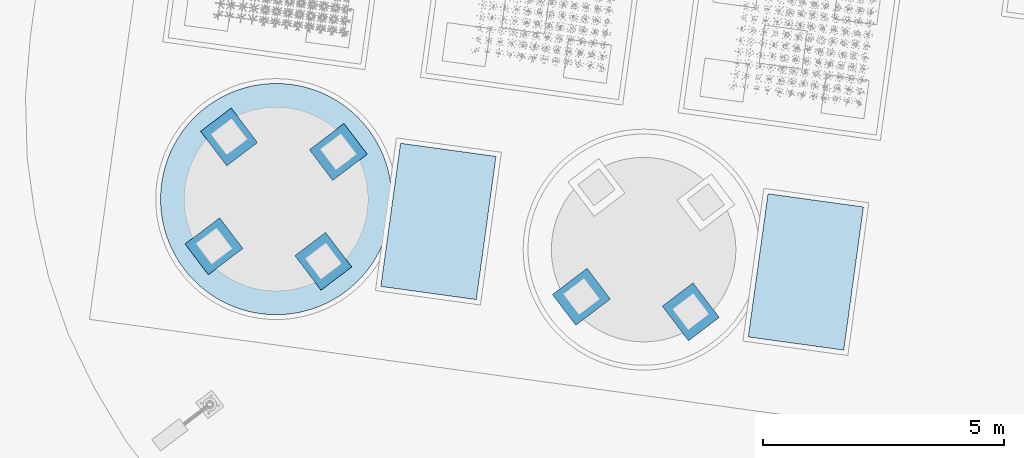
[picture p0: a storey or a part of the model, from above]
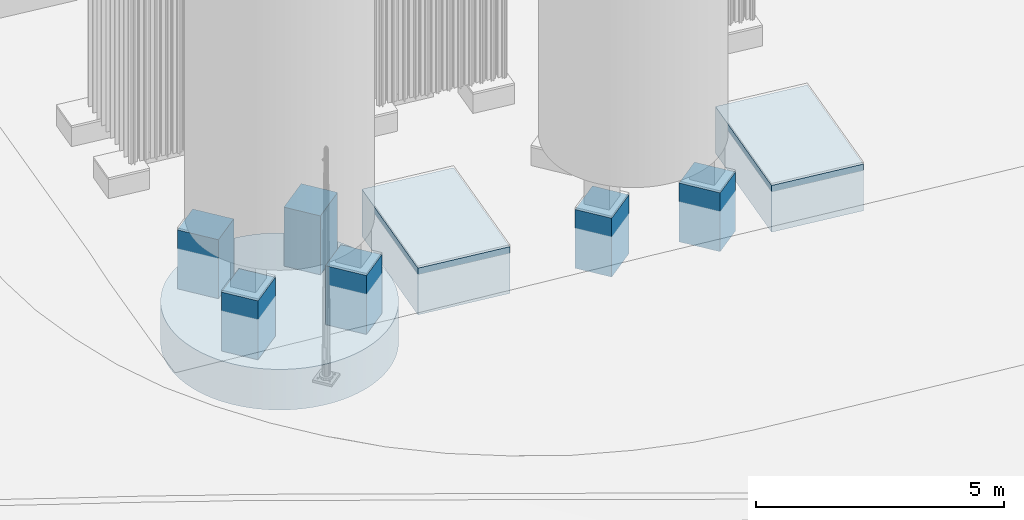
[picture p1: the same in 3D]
Properties of the parts of a building model (IFC4), part 1 of 134

# File
Description: Modelo BIM de planta completa con capas funcionales, componentes, acabados visuales y referencias geométricas identificadas.
File name: Jinhong_BIM.ifc
Time: 2026-09-07T22:02:33
Author: Equipo BIM de Jinhong
Organization: Jinhong Gas (España), S.L.
Written by: IfcOpenShell 0.8.5-1c5b825
Made in: IfcOpenShell 0.8.5-1c5b825
Authorization: Modelo de coordinación documental; pendiente de revisión profesional

# IfcProject, Planta de nitrógeno Jinhong — Mérida
Description: Reconstrucción BIM a partir de planos de arquitectura, estructura, urbanización y documentación de equipos. Información documentada, derivada y provisional diferenciada por elemento.; Document: Índice de tuberías de proceso; Fabricación y montaje de tuberías; Soldadura y ensayos no destructivos; Lavado y limpieza; Aislamiento térmico; Pintura; Pruebas de presión; Datos de líneas de proceso; Cuadro de aislamiento; Protección anticorrosiva; Materiales de tuberías; Implantación de equipos; Condiciones de cimentación; Planta general de tuberías de proceso; Plantas de tuberías por zonas; Índice de isométricos de proceso; Isométricos de proceso; Isométricos de agua; Isométricos del bastidor de proceso; Planta de estructuras metálicas; Soportes de equipos SL1201 y SL401/402; Soporte del bastidor de equipos; Soporte del bastidor de tuberías; Estructura de marquesina; Soportes especiales; Campana de aspiración; Soportes A01 y A02; Soportes estándar de tuberías; Plataformas de acceso; Escaleras de plataformas; Estructura de peldaños; Apertura automática de puerta; Plataforma móvil; Índice de tuberías de reserva; Fabricación y montaje de tuberías de reserva; Soldadura y ensayos no destructivos de reserva; Lavado y limpieza de reserva; Aislamiento térmico de reserva; Pintura de reserva; Pruebas de presión de reserva; Datos de líneas de reserva; Cuadro de aislamiento de reserva; Materiales de tuberías de reserva; Implantación de equipos de reserva; Condiciones de cimentación de reserva; Plantas de tuberías de reserva; Índice de isométricos de reserva; Isométricos de reserva; Isométricos del bastidor de reserva 1; Isométricos del bastidor de reserva 2; Planta de estructuras de reserva; Soportes A01 y A02 de reserva; Soportes especiales de reserva; Estructura del bastidor de reserva 1; Estructura del bastidor de reserva 2; Plano general del bastidor de reserva 1; Plano general del bastidor de reserva 2; Lista de soportes de reserva; Soportes estándar de reserva; Aislamiento de apoyos fríos; Índice de instrumentación; Diseño y montaje de instrumentación; Plantas generales de instrumentación; Plantas generales de instrumentación · copia de compatibilidad; Detalles de montaje de instrumentos; Distribución de aire de instrumentos; Puesta a tierra de instrumentos; Índice de planos eléctricos; Instrucciones eléctricas de diseño e instalación; Plano general eléctrico; Alumbrado de la caja fría; Esquema del cuadro de mantenimiento
JH_AlcanceDelModelo - Idioma: Español; Fase: Reconstrucción documental y coordinación preliminar; Limitaciones: Sin espacios interiores inventados ni redes MEP añadidas. Las prestaciones no verificadas se omiten.; CriterioDeMediciones: Cálculo de la geometría representada. Los volúmenes de envolventes y las dimensiones provisionales no son mediciones de obra, compra ni fabricación.; NúmeroDeElementos: 307

# IfcSite, Parcela industrial Jinhong
Description: Emplazamiento de la planta en Mérida; sistema de coordenadas ETRS89 / UTM 29N.
JH_Georreferenciacion - CRS: EPSG:25829; EsteDelOrigen: 729400 m; NorteDelOrigen: 4301550 m; CotaDelOrigen: 285 m; DatumVertical: Cotas de los planos; datum vertical pendiente de confirmación; Uso: Coordinación de la documentación disponible

# IfcBuilding (2)
Description: Edificio reconstruido a partir de planos; revisión documental y coordinación pendiente.
JH_DatosDelEdificio - CriterioDeSuperficie: Superficie exterior construida; no equivale a superficie útil ni a medición contractual; NoModelado: ["Particiones interiores con posición exacta, puertas interiores y aparatos sanitarios.","Instalaciones completas de agua, incendios, climatización, electricidad, cables e instrumentación.","Armaduras, placas y anclajes de conexión, detalle completo de correas y remates."]
Name | Document | IdentificadorDelEdificio | UsoDocumentado | CotaAbsolutaPavimentoTerminado (m) | SuperficieConstruidaDocumentada (m2) | FuenteDeSuperficie | Estado | SuperficieUtilDocumentada (m2) | IncidenciasPendientes
Sala de bombas contra incendios | Planos de arquitectura de la sala de bombas contra incendios | pump_house | Instalaciones de bombeo de agua contra incendios | 286.25 | 83.64 | {"documentId":"ARQ-SB-20260710","title":"Planos de arquitectura de la sala de bombas contra incendios","date":"2026-07-10","sheet":"A101 / p. 3; plano general URB-20260731, U004 / p. 5"} | Edificio representado en planos de arquitectura y estructura | 76.44 | ["Los cajetines de A108 y A201 conservan referencias de otro proyecto; la geometría se ha contrastado con A101.","A201 indica 300 mm de C25 sobre 100 mm de limpieza; el cuadro de materiales indica 200 mm de HA-25 sobre 80 mm de limpieza. El cajetín de A201 conserva una referencia a YUNENG ajena a este proyecto.","A110 indica antepecho de 1500 mm; otras secciones y alzados sugieren una cota menor. A110 titula la ventana C1290 y el cuadro A109 la identifica como C1226.","Las secciones también indican 284,75 m en la zona de zócalo y viga, frente a 284,85 m en la nota general. Ambas cotas requieren conciliación.","Los detalles de anclaje indican 10M30 y 12M30; la placa de base presenta cotas 650 y 750 mm no conciliadas. Anclajes y placas no modelados.","Depósito contra incendios: diámetro exterior de 6,50 m en el plano general, radio de 3,35 m en arquitectura y diámetro de cimentación de 6,00 m en estructura; requieren conciliación."]
Edificio de oficinas | Planos de arquitectura del edificio de oficinas | office | Administración, oficinas y servicios higiénicos | 285.95 | 200 | {"documentId":"ARQ-OF-20260710","title":"Planos de arquitectura del edificio de oficinas","date":"2026-07-10","sheet":"A101 / p. 3; plano general URB-20260731, U004 / p. 5"} | Oficina representada en el plano general; decisión de mantenerla pendiente de confirmación | 183.25 | ["El plano general de 2026-07-31 mantiene el edificio de oficinas de 200 m², mientras documentación anterior indica su supresión. Se conserva lo dibujado, pendiente de confirmación de la propiedad y del equipo de diseño.","Cubierta: arquitectura indica +4,400 m y el detalle estructural +4,450 m; espesores de placa 250 + 50 mm y 200 + 50 mm respectivamente. Se adopta el detalle estructural.","Pilares a +5,000 m según B102 y encuentro con cubierta a +4,450 m pendientes de coordinación.","Capas de fachada y cadena sur de huecos con diferencia de 100 mm pendientes de cotejo con CAD."]

# IfcBuildingStorey (2)
Description: Nivel de referencia del edificio. Las coordenadas de la geometría se conservan.
JH_DatosDelNivel - Nombre: Planta baja; Fuente: Planos de arquitectura y plano general U004
Name | In | Elevation (m) = CotaRelativaAlOrigen (m) | Document | CotaAbsolutaPavimentoTerminado (m)
Planta baja | Sala de bombas contra incendios | 1.25 | Planos de arquitectura de la sala de bombas contra incendios | 286.25
Planta baja | Edificio de oficinas | 0.95 | Planos de arquitectura del edificio de oficinas | 285.95

# IfcAnnotation: Plazas de aparcamiento · disposición ilustrativa
In: Parcela industrial Jinhong
Description: Entorno de coordinación: trazados derivados de las fuentes indicadas por elemento; cotas, espesores, acabados y mobiliario orientativos cuando no están documentados. No acredita propiedad, servidumbres ni cantidades de obra y no es una base de construcción.; Document: Indicación del cliente · entorno de 200 m con aparcamientos y luminarias ilustrativos; Entorno de Expacio Mérida · Catastro INSPIRE, PNOA y levantamiento Berrio; Levantamiento Berrio · parcelas I-27 Vial 3 e I-18 Vial 4; IGN · ortofotografía PNOA de máxima actualidad; Group: BIM · Entorno · aparcamientos y luminarias
JH_InformacionBIM - buildingId: context; buildingName: Entorno exterior de la parcela; level: Exterior · contexto de 200 m; category: Plazas de aparcamiento · disposición ilustrativa; ifcClass: IfcAnnotation; status: provisional; source: {"documentId":"JH-CLIENT-CONTEXT-20260909","title":"Indicación del cliente · entorno de 200 m con aparcamientos y luminarias ilustrativos","date":"2026-09-09","note":"Distribución aproximada autorizada. No acredita la posición ni el número real de plazas o farolas existentes."}; material: {"name":"Marcas de aparcamiento","status":"provisional","source":"Acabado visual aproximado; no especificación de proyecto."}; appearance: {"profileId":"ctx_mark","name":"Marcas de aparcamiento","status":"criterio_visual","basis":"Acabado de contexto orientativo, sin especificación de obra."}; dimensions: {"documented":[],"assumed":[{"label":"Largo de plaza","value":5.5,"unit":"m"},{"label":"Ancho de plaza","value":2.2,"unit":"m"},{"label":"Plazas representadas","value":16,"unit":"ud"}],"geometry":[]}; classification: {"layerId":"context_furniture","layerName":"Entorno · aparcamientos y luminarias","function":"Plazas de aparcamiento · disposición ilustrativa"}; visualLayer: {"id":"context_furniture","name":"Entorno · aparcamientos y luminarias","defaultVisible":false}; representationKind: entorno_ilustrativo; quantityEligible: no; positioning: {"Sistema":"ETRS89 / UTM 29N · metros","Origen del modelo":"X 729400 · Y 4301550 · Z 285 m","Alcance":"Hasta 200 m desde el lindero del proyecto; solo exterior de parcela","Planta":"Distribución ilustrativa autorizada","Altimetría":"Plano ajustado a 213 puntos XYZ de aceras, extrapolado al resto del contexto; no es un MDT levantado"}; issues: ["Contexto para lectura del emplazamiento; planta derivada de cartografía, cotas y detalles simplificados. No para construcción ni mediciones de obra.","Las mediciones en el entorno expresan la geometría representada y conservan la precisión de su fuente."]; conceptual: {"enabled":true,"basis":"Distribución aproximada autorizada. No acredita la posición ni el número real de plazas o farolas existentes.","pending":["Posición real del mobiliario","Dimensiones y niveles definitivos"]}; geometryMetrics: {"boundingBoxM":{"min":[-12.216745,64.501015,0.417411],"max":[-0.328879,175.189998,0.946724]},"extentsM":[11.887866,110.688983,0.529313],"meshSurfaceM2":58.382345,"meshVolumeM3":0.443541,"closedSolid":true,"basis":"Entorno de coordinación: trazados derivados de las fuentes indicadas por elemento; cotas, espesores, acabados y mobiliario orientativos cuando no están documentados. No acredita propiedad, servidumbres ni cantidades de obra y no es una base de construcción."}
JH_Trazabilidad - Origen: Indicación del cliente · entorno de 200 m con aparcamientos y luminarias ilustrativos; Estado: provisional; Capa BIM: Entorno · aparcamientos y luminarias; Mediciones de obra: Excluido; Identificador: CTX-PARKING; Categoria: Plazas de aparcamiento · disposición ilustrativa; ClaseIFC: IfcAnnotation; EstadoDeInformacion: provisional; DocumentoFuente: {"documentId":"JH-CLIENT-CONTEXT-20260909","title":"Indicación del cliente · entorno de 200 m con aparcamientos y luminarias ilustrativos","date":"2026-09-09","note":"Distribución aproximada autorizada. No acredita la posición ni el número real de plazas o farolas existentes."}; IncidenciasPendientes: ["Contexto para lectura del emplazamiento; planta derivada de cartografía, cotas y detalles simplificados. No para construcción ni mediciones de obra.","Las mediciones en el entorno expresan la geometría representada y conservan la precisión de su fuente."]; UsoDeLasMagnitudes: Entorno de coordinación: trazados derivados de las fuentes indicadas por elemento; cotas, espesores, acabados y mobiliario orientativos cuando no están documentados. No acredita propiedad, servidumbres ni cantidades de obra y no es una base de construcción.
JH_CriterioDePosicion - PosicionYEstado: {"Sistema":"ETRS89 / UTM 29N · metros","Origen del modelo":"X 729400 · Y 4301550 · Z 285 m","Alcance":"Hasta 200 m desde el lindero del proyecto; solo exterior de parcela","Planta":"Distribución ilustrativa autorizada","Altimetría":"Plano ajustado a 213 puntos XYZ de aceras, extrapolado al resto del contexto; no es un MDT levantado"}
JH_EvidenciaDeMaterial - name: Marcas de aparcamiento; status: provisional; source: Acabado visual aproximado; no especificación de proyecto.
JH_CapaBIM - IdentificadorCapa: context_furniture; NombreCapa: Entorno · aparcamientos y luminarias; Funcion: Plazas de aparcamiento · disposición ilustrativa; VisibilidadInicial: no
JH_EntornoContexto - Estado: provisional; Origen: {"documentId":"JH-CLIENT-CONTEXT-20260909","title":"Indicación del cliente · entorno de 200 m con aparcamientos y luminarias ilustrativos","date":"2026-09-09","note":"Distribución aproximada autorizada. No acredita la posición ni el número real de plazas o farolas existentes."}; Posicion: {"Sistema":"ETRS89 / UTM 29N · metros","Origen del modelo":"X 729400 · Y 4301550 · Z 285 m","Alcance":"Hasta 200 m desde el lindero del proyecto; solo exterior de parcela","Planta":"Distribución ilustrativa autorizada","Altimetría":"Plano ajustado a 213 puntos XYZ de aceras, extrapolado al resto del contexto; no es un MDT levantado"}; DimensionesSupuestas: [{"label":"Largo de plaza","value":5.5,"unit":"m"},{"label":"Ancho de plaza","value":2.2,"unit":"m"},{"label":"Plazas representadas","value":16,"unit":"ud"}]; IncluirEnMediciones: no; EsquemaIlustrativo: yes; Criterio: Entorno de coordinación: trazados derivados de las fuentes indicadas por elemento; cotas, espesores, acabados y mobiliario orientativos cuando no están documentados. No acredita propiedad, servidumbres ni cantidades de obra y no es una base de construcción.
JH_EsquemaProvisional - Estado: No para construcción; Origen: {"documentId":"JH-CLIENT-CONTEXT-20260909","title":"Indicación del cliente · entorno de 200 m con aparcamientos y luminarias ilustrativos","date":"2026-09-09","note":"Distribución aproximada autorizada. No acredita la posición ni el número real de plazas o farolas existentes."}; DimensionesSupuestas: [{"label":"Largo de plaza","value":5.5,"unit":"m"},{"label":"Ancho de plaza","value":2.2,"unit":"m"},{"label":"Plazas representadas","value":16,"unit":"ud"}]; Posicion: {"Sistema":"ETRS89 / UTM 29N · metros","Origen del modelo":"X 729400 · Y 4301550 · Z 285 m","Alcance":"Hasta 200 m desde el lindero del proyecto; solo exterior de parcela","Planta":"Distribución ilustrativa autorizada","Altimetría":"Plano ajustado a 213 puntos XYZ de aceras, extrapolado al resto del contexto; no es un MDT levantado"}; IncluirEnMediciones: no; Criterio: {"enabled":true,"basis":"Distribución aproximada autorizada. No acredita la posición ni el número real de plazas o farolas existentes.","pending":["Posición real del mobiliario","Dimensiones y niveles definitivos"]}

# IfcBeam (24)
In: Planta baja
Description: Viga; PredefinedType: BEAM
JH_InformacionBIM - level: Planta baja; category: Viga; ifcClass: IfcBeam; componentSeparation: {"status":"objeto_independiente","note":"Control de visibilidad del objeto completo; la clasificación no altera la malla."}
JH_Trazabilidad - Sistema de coordenadas: Coordenadas de proyecto en metros; sumar (729400, 4301550, 285) para recuperar las coordenadas UTM y cotas de los planos.; Uso del modelo: Reconstrucción tridimensional de la documentación y revisión preliminar de coordinación; pendiente de revisión por el equipo de diseño.; Verificación de la malla: Malla cerrada, orientación coherente de las caras y volumen positivo.; Referencia de implantación: Plano general U004 de 2026-07-31; geometría vectorial del PDF registrada con las coordenadas de lindero indicadas.; Clase IFC: IfcBeam; Fase del modelo: V0.1 · Reconstrucción documental y coordinación preliminar; Representación geométrica: Sólido de malla triangular cerrada en IFC4; Aplicabilidad de las mediciones: Volumen exclusivamente geométrico; los espesores de representación, las simplificaciones y las envolventes no constituyen mediciones de compra, ejecución, fabricación ni volumen neto de material.; Estado del acabado: criterio_visual; Categoria: Viga; ClaseIFC: IfcBeam; UsoDeLasMagnitudes: Geometría de coordinación. Los volúmenes de referencia y subcomponentes no son cantidades de material ni componentes de fabricación certificados.
JH_EvidenciaDeMaterial - status: known
JH_CapaBIM - Funcion: Viga; VisibilidadInicial: yes
JH_AcabadoVisual - Estado: criterio_visual; Nota: La apariencia no certifica el material físico ni el acabado de fabricación.
Name | Document | Material = JH_Trazabilidad, Material = name | Dimensiones de la caja local del elemento (X, Y, Z) | Cota mínima absoluta de la malla (m) | Cota máxima absoluta de la malla (m) | Volumen geométrico bruto (m3) = Volumen geométrico (m³) | Reference = Identificador del elemento = Identificador | ExtensionX (m) | ExtensionY (m) | ExtensionZ (m) | SuperficieDeLaMalla (m2) | VolumenGeometrico (m3) = GrossVolume (m3) | buildingId | buildingName = Edificio | material | dimensions | JH_InformacionBIM, source = DocumentoFuente | status = EstadoDeInformacion | issues = IncidenciasPendientes | positioning = PosicionYEstado | geometryMetrics | ifcAssociations | visualLayer | materialAppearance | visualizationIdentity | classification | layerId = IdentificadorCapa | appearance | Planos de referencia | Base geométrica | Perfil laminado = JH_DimensionesDocumentadas, Perfil | Catálogo del perfil | Página PDF del catálogo | Acuerdos del perfil | Extremos y uniones | Coordinación de cotas pendiente | Estado de la implantación | Disciplina | Referencia del material = JH_EvidenciaDeMaterial, source | Cota de planta baja terminada (m) | Capa BIM = NombreCapa | Acabado de visualización = Acabado | Canto nominal del perfil | Anchura nominal de ala | Espesor nominal de alma | Espesor nominal de ala | JH_AcabadoVisual, Perfil | ColorRGB | Rugosidad | Metallicidad | Referencia | Group | Discrepancia entre versiones
Sala de bombas contra incendios · viga de cubierta IPE500 · 1 | Planos de estructura de la sala de bombas contra incendios; Planos de estructura de la sala de bombas contra incendios | Acero estructural S355JR | 9.5 × 0.2 × 0.5 | 290.738 | 291.238 | 0.106149 | pump_house_0052 | 9.43871 | 1.49207 | 0.5 | 16.9286 | 0.106149 | pump_house | Sala de bombas contra incendios | {"name":"Acero estructural S355JR","source":"EST-SB-20260710 · Estructura A101 / p. 2, Arquitectura A103 / p. 5","status":"known"} | {"documented":[{"label":"Perfil","value":"IPE500","unit":"designación","source":"EST-SB-20260710 · Estructura A101 / p. 2, Arquitectura A103 / p. 5","status":"documentado"},{"label":"Canto nominal del perfil","value":500,"unit":"mm","source":"Catálogo de perfiles ArcelorMittal · 76","status":"documentado"},{"label":"Anchura nominal de ala","value":200,"unit":"mm","source":"Catálogo de perfiles ArcelorMittal · 76","status":"documentado"},{"label":"Espesor nominal de alma","value":10.2,"unit":"mm","source":"Catálogo de perfiles ArcelorMittal · 76","status":"documentado"},{"label":"Espesor nominal de ala","value":16,"unit":"mm","source":"Catálogo de perfiles ArcelorMittal · 76","status":"documentado"}],"geometry":[{"label":"Dimensiones de la caja local del elemento (X, Y, Z)","value":"9.5 × 0.2 × 0.5","unit":"m","source":"Malla triangulada del elemento en ejes locales del edificio","status":"derivado"},{"label":"Cota mínima absoluta de la malla","value":290.7375,"unit":"m","source":"Malla de proyecto y origen altimétrico 285 m","status":"derivado"},{"label":"Cota máxima absoluta de la malla","value":291.2375,"unit":"m","source":"Malla de proyecto y origen altimétrico 285 m","status":"derivado"},{"label":"Volumen geométrico bruto","value":0.106149,"unit":"m³","source":"Malla cerrada del elemento","status":"derivado"}],"notes":["Las dimensiones documentadas proceden de anotaciones o cuadros; la caja y el volumen se calculan a partir de la malla.","El volumen es exclusivamente geométrico y bruto; no representa una medición neta de material ni una cantidad de compra."]} | {"documentId":"EST-SB-20260710","title":"Planos de estructura de la sala de bombas contra incendios","date":"2026-07-10","sheet":"Estructura A101 / p. 2, Arquitectura A103 / p. 5"} | provisional | ["En bombas, la cabeza de viga sigue el plano de pilares con pendiente del 5 %. En oficinas, se adopta cabeza de viga a +4,200 m bajo la placa; el encuentro con pilares a +5,000 m requiere revisión.","Ejes unidos a centros de pilares o vigas; chapas de unión y longitudes libres sin desarrollar.","Acuerdos de unión entre alma y alas omitidos.","Registro de líneas del PDF general con envolvente de 10,2 × 8,2 m. Estimación de trabajo de implantación de ±0,15 m, pendiente de CAD nativo; no constituye una precisión topográfica garantizada."] | {"horizontalStatus":"derivado","verticalStatus":"provisional","baseElevationM":286.25,"note":"Registro de líneas del PDF general con envolvente de 10,2 × 8,2 m. Estimación de trabajo de implantación de ±0,15 m, pendiente de CAD nativo; no constituye una precisión topográfica garantizada."} | {"boundingBoxM":{"min":[8.496881,25.69991,5.7375],"max":[17.93559,27.191984,6.2375]},"extentsM":[9.438709,1.492074,0.5],"meshSurfaceM2":16.928561,"meshVolumeM3":0.106149,"closedSolid":true,"basis":"Geometría triangulada releída del IFC; envolventes y magnitudes no contractuales."} | {"material":true,"document":true,"quantities":true,"containerGuid":"0Wh59pm9LO_einrwiq6Es1","containerName":"Planta baja"} | {"id":"structure","name":"Estructura"} | {"profileId":"steel_structural","name":"Acero estructural · protección gris","materialName":"Acero estructural S355JR","physicalMaterialStatus":"known","physicalMaterialSource":"EST-SB-20260710 · Estructura A101 / p. 2, Arquitectura A103 / p. 5","appearanceStatus":"criterio_visual","appearanceBasis":"S355JR consta en la documentación; protección superficial gris adoptada para visualización, sin especificación de pintura confirmada.","note":"La apariencia gráfica no modifica ni confirma la especificación física del material."} | {"elementId":"pump_house_0052","ifcGuid":"2nmUP$19jOEBoxNlUrdHAE","ifcClass":"IfcBeam","buildingId":"pump_house","buildingName":"Sala de bombas contra incendios","sourceDocumentId":"EST-SB-20260710","sourceRepresentationKind":"documentary_mesh"} | {"layerId":"structure","layerName":"Estructura","role":"Viga","basis":"Clasificación por función del elemento; no modifica las especificaciones documentales."} | structure | {"profileId":"steel_structural","name":"Acero estructural · protección gris","status":"criterio_visual","basis":"S355JR consta en la documentación; protección superficial gris adoptada para visualización, sin especificación de pintura confirmada.","physicalMaterialUnchanged":true} | EST-SB-20260710 · Estructura A101 / p. 2, Arquitectura A103 / p. 5 | Perfil y dimensiones XY documentados o deducidos; cota de viga deducida de la cabeza de pilar o del intradós de la placa prefabricada. | IPE500 | https://sections.arcelormittal.com/repository2/Sections/5_1_5_ArcelorMittal_FR_EN_RU_web.pdf | 76 | Acuerdos de unión entre alma y alas omitidos. | Ejes unidos a centros de pilares o vigas; chapas de unión y longitudes libres sin desarrollar. | En bombas, la cabeza de viga sigue el plano de pilares con pendiente del 5 %. En oficinas, se adopta cabeza de viga a +4,200 m bajo la placa; el encuentro con pilares a +5,000 m requiere revisión. | Registro de líneas del PDF general con envolvente de 10,2 × 8,2 m. Estimación de trabajo de implantación de ±0,15 m, pendiente de CAD nativo; no constituye una precisión topográfica garantizada. | Estructura | EST-SB-20260710 · Estructura A101 / p. 2, Arquitectura A103 / p. 5 | 286.25 | Estructura | Acero estructural · protección gris | 500 | 200 | 10.2 | 16 | steel_structural | [0.396078,0.454902,0.482353] | 0.52 | 0.35 | S355JR consta en la documentación; protección superficial gris adoptada para visualización, sin especificación de pintura confirmada. | Estructura; BIM · Estructura
Sala de bombas contra incendios · viga de cubierta IPE500 · 2 | Planos de estructura de la sala de bombas contra incendios; Planos de estructura de la sala de bombas contra incendios | Acero estructural S355JR | 9.5 × 0.2 × 0.5 | 290.363 | 290.863 | 0.106149 | pump_house_0053 | 9.43871 | 1.49207 | 0.5 | 16.9286 | 0.106149 | pump_house | Sala de bombas contra incendios | {"name":"Acero estructural S355JR","source":"EST-SB-20260710 · Estructura A101 / p. 2, Arquitectura A103 / p. 5","status":"known"} | {"documented":[{"label":"Perfil","value":"IPE500","unit":"designación","source":"EST-SB-20260710 · Estructura A101 / p. 2, Arquitectura A103 / p. 5","status":"documentado"},{"label":"Canto nominal del perfil","value":500,"unit":"mm","source":"Catálogo de perfiles ArcelorMittal · 76","status":"documentado"},{"label":"Anchura nominal de ala","value":200,"unit":"mm","source":"Catálogo de perfiles ArcelorMittal · 76","status":"documentado"},{"label":"Espesor nominal de alma","value":10.2,"unit":"mm","source":"Catálogo de perfiles ArcelorMittal · 76","status":"documentado"},{"label":"Espesor nominal de ala","value":16,"unit":"mm","source":"Catálogo de perfiles ArcelorMittal · 76","status":"documentado"}],"geometry":[{"label":"Dimensiones de la caja local del elemento (X, Y, Z)","value":"9.5 × 0.2 × 0.5","unit":"m","source":"Malla triangulada del elemento en ejes locales del edificio","status":"derivado"},{"label":"Cota mínima absoluta de la malla","value":290.3625,"unit":"m","source":"Malla de proyecto y origen altimétrico 285 m","status":"derivado"},{"label":"Cota máxima absoluta de la malla","value":290.8625,"unit":"m","source":"Malla de proyecto y origen altimétrico 285 m","status":"derivado"},{"label":"Volumen geométrico bruto","value":0.106149,"unit":"m³","source":"Malla cerrada del elemento","status":"derivado"}],"notes":["Las dimensiones documentadas proceden de anotaciones o cuadros; la caja y el volumen se calculan a partir de la malla.","El volumen es exclusivamente geométrico y bruto; no representa una medición neta de material ni una cantidad de compra."]} | {"documentId":"EST-SB-20260710","title":"Planos de estructura de la sala de bombas contra incendios","date":"2026-07-10","sheet":"Estructura A101 / p. 2, Arquitectura A103 / p. 5"} | provisional | ["En bombas, la cabeza de viga sigue el plano de pilares con pendiente del 5 %. En oficinas, se adopta cabeza de viga a +4,200 m bajo la placa; el encuentro con pilares a +5,000 m requiere revisión.","Ejes unidos a centros de pilares o vigas; chapas de unión y longitudes libres sin desarrollar.","Acuerdos de unión entre alma y alas omitidos.","Registro de líneas del PDF general con envolvente de 10,2 × 8,2 m. Estimación de trabajo de implantación de ±0,15 m, pendiente de CAD nativo; no constituye una precisión topográfica garantizada."] | {"horizontalStatus":"derivado","verticalStatus":"provisional","baseElevationM":286.25,"note":"Registro de líneas del PDF general con envolvente de 10,2 × 8,2 m. Estimación de trabajo de implantación de ±0,15 m, pendiente de CAD nativo; no constituye una precisión topográfica garantizada."} | {"boundingBoxM":{"min":[9.51841,33.130016,5.3625],"max":[18.957119,34.62209,5.8625]},"extentsM":[9.438709,1.492074,0.5],"meshSurfaceM2":16.928561,"meshVolumeM3":0.106149,"closedSolid":true,"basis":"Geometría triangulada releída del IFC; envolventes y magnitudes no contractuales."} | {"material":true,"document":true,"quantities":true,"containerGuid":"0Wh59pm9LO_einrwiq6Es1","containerName":"Planta baja"} | {"id":"structure","name":"Estructura"} | {"profileId":"steel_structural","name":"Acero estructural · protección gris","materialName":"Acero estructural S355JR","physicalMaterialStatus":"known","physicalMaterialSource":"EST-SB-20260710 · Estructura A101 / p. 2, Arquitectura A103 / p. 5","appearanceStatus":"criterio_visual","appearanceBasis":"S355JR consta en la documentación; protección superficial gris adoptada para visualización, sin especificación de pintura confirmada.","note":"La apariencia gráfica no modifica ni confirma la especificación física del material."} | {"elementId":"pump_house_0053","ifcGuid":"1QwL79DtXH2wnZYJAhHU2F","ifcClass":"IfcBeam","buildingId":"pump_house","buildingName":"Sala de bombas contra incendios","sourceDocumentId":"EST-SB-20260710","sourceRepresentationKind":"documentary_mesh"} | {"layerId":"structure","layerName":"Estructura","role":"Viga","basis":"Clasificación por función del elemento; no modifica las especificaciones documentales."} | structure | {"profileId":"steel_structural","name":"Acero estructural · protección gris","status":"criterio_visual","basis":"S355JR consta en la documentación; protección superficial gris adoptada para visualización, sin especificación de pintura confirmada.","physicalMaterialUnchanged":true} | EST-SB-20260710 · Estructura A101 / p. 2, Arquitectura A103 / p. 5 | Perfil y dimensiones XY documentados o deducidos; cota de viga deducida de la cabeza de pilar o del intradós de la placa prefabricada. | IPE500 | https://sections.arcelormittal.com/repository2/Sections/5_1_5_ArcelorMittal_FR_EN_RU_web.pdf | 76 | Acuerdos de unión entre alma y alas omitidos. | Ejes unidos a centros de pilares o vigas; chapas de unión y longitudes libres sin desarrollar. | En bombas, la cabeza de viga sigue el plano de pilares con pendiente del 5 %. En oficinas, se adopta cabeza de viga a +4,200 m bajo la placa; el encuentro con pilares a +5,000 m requiere revisión. | Registro de líneas del PDF general con envolvente de 10,2 × 8,2 m. Estimación de trabajo de implantación de ±0,15 m, pendiente de CAD nativo; no constituye una precisión topográfica garantizada. | Estructura | EST-SB-20260710 · Estructura A101 / p. 2, Arquitectura A103 / p. 5 | 286.25 | Estructura | Acero estructural · protección gris | 500 | 200 | 10.2 | 16 | steel_structural | [0.396078,0.454902,0.482353] | 0.52 | 0.35 | S355JR consta en la documentación; protección superficial gris adoptada para visualización, sin especificación de pintura confirmada. | Estructura; BIM · Estructura
Sala de bombas contra incendios · viga de cubierta IPE500 · 3 | Planos de estructura de la sala de bombas contra incendios; Planos de estructura de la sala de bombas contra incendios | Acero estructural S355JR | 0.2 × 7.52497 × 0.874376 | 290.363 | 291.237 | 0.083907 | pump_house_0054 | 1.22307 | 7.48208 | 0.874376 | 13.386 | 0.0839067 | pump_house | Sala de bombas contra incendios | {"name":"Acero estructural S355JR","source":"EST-SB-20260710 · Estructura A101 / p. 2, Arquitectura A103 / p. 5","status":"known"} | {"documented":[{"label":"Perfil","value":"IPE500","unit":"designación","source":"EST-SB-20260710 · Estructura A101 / p. 2, Arquitectura A103 / p. 5","status":"documentado"},{"label":"Canto nominal del perfil","value":500,"unit":"mm","source":"Catálogo de perfiles ArcelorMittal · 76","status":"documentado"},{"label":"Anchura nominal de ala","value":200,"unit":"mm","source":"Catálogo de perfiles ArcelorMittal · 76","status":"documentado"},{"label":"Espesor nominal de alma","value":10.2,"unit":"mm","source":"Catálogo de perfiles ArcelorMittal · 76","status":"documentado"},{"label":"Espesor nominal de ala","value":16,"unit":"mm","source":"Catálogo de perfiles ArcelorMittal · 76","status":"documentado"}],"geometry":[{"label":"Dimensiones de la caja local del elemento (X, Y, Z)","value":"0.2 × 7.52497 × 0.874376","unit":"m","source":"Malla triangulada del elemento en ejes locales del edificio","status":"derivado"},{"label":"Cota mínima absoluta de la malla","value":290.362812,"unit":"m","source":"Malla de proyecto y origen altimétrico 285 m","status":"derivado"},{"label":"Cota máxima absoluta de la malla","value":291.237188,"unit":"m","source":"Malla de proyecto y origen altimétrico 285 m","status":"derivado"},{"label":"Volumen geométrico bruto","value":0.083907,"unit":"m³","source":"Malla cerrada del elemento","status":"derivado"}],"notes":["Las dimensiones documentadas proceden de anotaciones o cuadros; la caja y el volumen se calculan a partir de la malla.","El volumen es exclusivamente geométrico y bruto; no representa una medición neta de material ni una cantidad de compra."]} | {"documentId":"EST-SB-20260710","title":"Planos de estructura de la sala de bombas contra incendios","date":"2026-07-10","sheet":"Estructura A101 / p. 2, Arquitectura A103 / p. 5"} | provisional | ["En bombas, la cabeza de viga sigue el plano de pilares con pendiente del 5 %. En oficinas, se adopta cabeza de viga a +4,200 m bajo la placa; el encuentro con pilares a +5,000 m requiere revisión.","Ejes unidos a centros de pilares o vigas; chapas de unión y longitudes libres sin desarrollar.","Acuerdos de unión entre alma y alas omitidos.","Registro de líneas del PDF general con envolvente de 10,2 × 8,2 m. Estimación de trabajo de implantación de ±0,15 m, pendiente de CAD nativo; no constituye una precisión topográfica garantizada."] | {"horizontalStatus":"derivado","verticalStatus":"provisional","baseElevationM":286.25,"note":"Registro de líneas del PDF general con envolvente de 10,2 × 8,2 m. Estimación de trabajo de implantación de ±0,15 m, pendiente de CAD nativo; no constituye una precisión topográfica garantizada."} | {"boundingBoxM":{"min":[8.409733,27.066928,5.362812],"max":[9.632799,34.54901,6.237188]},"extentsM":[1.223066,7.482082,0.874376],"meshSurfaceM2":13.386016,"meshVolumeM3":0.083907,"closedSolid":true,"basis":"Geometría triangulada releída del IFC; envolventes y magnitudes no contractuales."} | {"material":true,"document":true,"quantities":true,"containerGuid":"0Wh59pm9LO_einrwiq6Es1","containerName":"Planta baja"} | {"id":"structure","name":"Estructura"} | {"profileId":"steel_structural","name":"Acero estructural · protección gris","materialName":"Acero estructural S355JR","physicalMaterialStatus":"known","physicalMaterialSource":"EST-SB-20260710 · Estructura A101 / p. 2, Arquitectura A103 / p. 5","appearanceStatus":"criterio_visual","appearanceBasis":"S355JR consta en la documentación; protección superficial gris adoptada para visualización, sin especificación de pintura confirmada.","note":"La apariencia gráfica no modifica ni confirma la especificación física del material."} | {"elementId":"pump_house_0054","ifcGuid":"2_ukjE47zMMOWZzmbgM$3J","ifcClass":"IfcBeam","buildingId":"pump_house","buildingName":"Sala de bombas contra incendios","sourceDocumentId":"EST-SB-20260710","sourceRepresentationKind":"documentary_mesh"} | {"layerId":"structure","layerName":"Estructura","role":"Viga","basis":"Clasificación por función del elemento; no modifica las especificaciones documentales."} | structure | {"profileId":"steel_structural","name":"Acero estructural · protección gris","status":"criterio_visual","basis":"S355JR consta en la documentación; protección superficial gris adoptada para visualización, sin especificación de pintura confirmada.","physicalMaterialUnchanged":true} | EST-SB-20260710 · Estructura A101 / p. 2, Arquitectura A103 / p. 5 | Perfil y dimensiones XY documentados o deducidos; cota de viga deducida de la cabeza de pilar o del intradós de la placa prefabricada. | IPE500 | https://sections.arcelormittal.com/repository2/Sections/5_1_5_ArcelorMittal_FR_EN_RU_web.pdf | 76 | Acuerdos de unión entre alma y alas omitidos. | Ejes unidos a centros de pilares o vigas; chapas de unión y longitudes libres sin desarrollar. | En bombas, la cabeza de viga sigue el plano de pilares con pendiente del 5 %. En oficinas, se adopta cabeza de viga a +4,200 m bajo la placa; el encuentro con pilares a +5,000 m requiere revisión. | Registro de líneas del PDF general con envolvente de 10,2 × 8,2 m. Estimación de trabajo de implantación de ±0,15 m, pendiente de CAD nativo; no constituye una precisión topográfica garantizada. | Estructura | EST-SB-20260710 · Estructura A101 / p. 2, Arquitectura A103 / p. 5 | 286.25 | Estructura | Acero estructural · protección gris | 500 | 200 | 10.2 | 16 | steel_structural | [0.396078,0.454902,0.482353] | 0.52 | 0.35 | S355JR consta en la documentación; protección superficial gris adoptada para visualización, sin especificación de pintura confirmada. | Estructura; BIM · Estructura
Sala de bombas contra incendios · viga de cubierta IPE500 · 4 | Planos de estructura de la sala de bombas contra incendios; Planos de estructura de la sala de bombas contra incendios | Acero estructural S355JR | 0.2 × 7.52497 × 0.874376 | 290.363 | 291.237 | 0.083907 | pump_house_0055 | 1.22307 | 7.48208 | 0.874376 | 13.386 | 0.0839066 | pump_house | Sala de bombas contra incendios | {"name":"Acero estructural S355JR","source":"EST-SB-20260710 · Estructura A101 / p. 2, Arquitectura A103 / p. 5","status":"known"} | {"documented":[{"label":"Perfil","value":"IPE500","unit":"designación","source":"EST-SB-20260710 · Estructura A101 / p. 2, Arquitectura A103 / p. 5","status":"documentado"},{"label":"Canto nominal del perfil","value":500,"unit":"mm","source":"Catálogo de perfiles ArcelorMittal · 76","status":"documentado"},{"label":"Anchura nominal de ala","value":200,"unit":"mm","source":"Catálogo de perfiles ArcelorMittal · 76","status":"documentado"},{"label":"Espesor nominal de alma","value":10.2,"unit":"mm","source":"Catálogo de perfiles ArcelorMittal · 76","status":"documentado"},{"label":"Espesor nominal de ala","value":16,"unit":"mm","source":"Catálogo de perfiles ArcelorMittal · 76","status":"documentado"}],"geometry":[{"label":"Dimensiones de la caja local del elemento (X, Y, Z)","value":"0.2 × 7.52497 × 0.874376","unit":"m","source":"Malla triangulada del elemento en ejes locales del edificio","status":"derivado"},{"label":"Cota mínima absoluta de la malla","value":290.362812,"unit":"m","source":"Malla de proyecto y origen altimétrico 285 m","status":"derivado"},{"label":"Cota máxima absoluta de la malla","value":291.237188,"unit":"m","source":"Malla de proyecto y origen altimétrico 285 m","status":"derivado"},{"label":"Volumen geométrico bruto","value":0.083907,"unit":"m³","source":"Malla cerrada del elemento","status":"derivado"}],"notes":["Las dimensiones documentadas proceden de anotaciones o cuadros; la caja y el volumen se calculan a partir de la malla.","El volumen es exclusivamente geométrico y bruto; no representa una medición neta de material ni una cantidad de compra."]} | {"documentId":"EST-SB-20260710","title":"Planos de estructura de la sala de bombas contra incendios","date":"2026-07-10","sheet":"Estructura A101 / p. 2, Arquitectura A103 / p. 5"} | provisional | ["En bombas, la cabeza de viga sigue el plano de pilares con pendiente del 5 %. En oficinas, se adopta cabeza de viga a +4,200 m bajo la placa; el encuentro con pilares a +5,000 m requiere revisión.","Ejes unidos a centros de pilares o vigas; chapas de unión y longitudes libres sin desarrollar.","Acuerdos de unión entre alma y alas omitidos.","Registro de líneas del PDF general con envolvente de 10,2 × 8,2 m. Estimación de trabajo de implantación de ±0,15 m, pendiente de CAD nativo; no constituye una precisión topográfica garantizada."] | {"horizontalStatus":"derivado","verticalStatus":"provisional","baseElevationM":286.25,"note":"Registro de líneas del PDF general con envolvente de 10,2 × 8,2 m. Estimación de trabajo de implantación de ±0,15 m, pendiente de CAD nativo; no constituye una precisión topográfica garantizada."} | {"boundingBoxM":{"min":[17.821201,25.77299,5.362812],"max":[19.044267,33.255072,6.237188]},"extentsM":[1.223066,7.482082,0.874376],"meshSurfaceM2":13.386016,"meshVolumeM3":0.083907,"closedSolid":true,"basis":"Geometría triangulada releída del IFC; envolventes y magnitudes no contractuales."} | {"material":true,"document":true,"quantities":true,"containerGuid":"0Wh59pm9LO_einrwiq6Es1","containerName":"Planta baja"} | {"id":"structure","name":"Estructura"} | {"profileId":"steel_structural","name":"Acero estructural · protección gris","materialName":"Acero estructural S355JR","physicalMaterialStatus":"known","physicalMaterialSource":"EST-SB-20260710 · Estructura A101 / p. 2, Arquitectura A103 / p. 5","appearanceStatus":"criterio_visual","appearanceBasis":"S355JR consta en la documentación; protección superficial gris adoptada para visualización, sin especificación de pintura confirmada.","note":"La apariencia gráfica no modifica ni confirma la especificación física del material."} | {"elementId":"pump_house_0055","ifcGuid":"3pY_oXA7bIrA2kxOyf7rJF","ifcClass":"IfcBeam","buildingId":"pump_house","buildingName":"Sala de bombas contra incendios","sourceDocumentId":"EST-SB-20260710","sourceRepresentationKind":"documentary_mesh"} | {"layerId":"structure","layerName":"Estructura","role":"Viga","basis":"Clasificación por función del elemento; no modifica las especificaciones documentales."} | structure | {"profileId":"steel_structural","name":"Acero estructural · protección gris","status":"criterio_visual","basis":"S355JR consta en la documentación; protección superficial gris adoptada para visualización, sin especificación de pintura confirmada.","physicalMaterialUnchanged":true} | EST-SB-20260710 · Estructura A101 / p. 2, Arquitectura A103 / p. 5 | Perfil y dimensiones XY documentados o deducidos; cota de viga deducida de la cabeza de pilar o del intradós de la placa prefabricada. | IPE500 | https://sections.arcelormittal.com/repository2/Sections/5_1_5_ArcelorMittal_FR_EN_RU_web.pdf | 76 | Acuerdos de unión entre alma y alas omitidos. | Ejes unidos a centros de pilares o vigas; chapas de unión y longitudes libres sin desarrollar. | En bombas, la cabeza de viga sigue el plano de pilares con pendiente del 5 %. En oficinas, se adopta cabeza de viga a +4,200 m bajo la placa; el encuentro con pilares a +5,000 m requiere revisión. | Registro de líneas del PDF general con envolvente de 10,2 × 8,2 m. Estimación de trabajo de implantación de ±0,15 m, pendiente de CAD nativo; no constituye una precisión topográfica garantizada. | Estructura | EST-SB-20260710 · Estructura A101 / p. 2, Arquitectura A103 / p. 5 | 286.25 | Estructura | Acero estructural · protección gris | 500 | 200 | 10.2 | 16 | steel_structural | [0.396078,0.454902,0.482353] | 0.52 | 0.35 | S355JR consta en la documentación; protección superficial gris adoptada para visualización, sin especificación de pintura confirmada. | Estructura; BIM · Estructura
Sala de bombas contra incendios · viga de cubierta IPE500 · 5 | Planos de estructura de la sala de bombas contra incendios; Planos de estructura de la sala de bombas contra incendios | Acero estructural S355JR | 0.2 × 7.52497 × 0.874376 | 290.363 | 291.237 | 0.083907 | pump_house_0056 | 1.22307 | 7.48208 | 0.874376 | 13.386 | 0.0839068 | pump_house | Sala de bombas contra incendios | {"name":"Acero estructural S355JR","source":"EST-SB-20260710 · Estructura A101 / p. 2, Arquitectura A103 / p. 5","status":"known"} | {"documented":[{"label":"Perfil","value":"IPE500","unit":"designación","source":"EST-SB-20260710 · Estructura A101 / p. 2, Arquitectura A103 / p. 5","status":"documentado"},{"label":"Canto nominal del perfil","value":500,"unit":"mm","source":"Catálogo de perfiles ArcelorMittal · 76","status":"documentado"},{"label":"Anchura nominal de ala","value":200,"unit":"mm","source":"Catálogo de perfiles ArcelorMittal · 76","status":"documentado"},{"label":"Espesor nominal de alma","value":10.2,"unit":"mm","source":"Catálogo de perfiles ArcelorMittal · 76","status":"documentado"},{"label":"Espesor nominal de ala","value":16,"unit":"mm","source":"Catálogo de perfiles ArcelorMittal · 76","status":"documentado"}],"geometry":[{"label":"Dimensiones de la caja local del elemento (X, Y, Z)","value":"0.2 × 7.52497 × 0.874376","unit":"m","source":"Malla triangulada del elemento en ejes locales del edificio","status":"derivado"},{"label":"Cota mínima absoluta de la malla","value":290.362812,"unit":"m","source":"Malla de proyecto y origen altimétrico 285 m","status":"derivado"},{"label":"Cota máxima absoluta de la malla","value":291.237188,"unit":"m","source":"Malla de proyecto y origen altimétrico 285 m","status":"derivado"},{"label":"Volumen geométrico bruto","value":0.083907,"unit":"m³","source":"Malla cerrada del elemento","status":"derivado"}],"notes":["Las dimensiones documentadas proceden de anotaciones o cuadros; la caja y el volumen se calculan a partir de la malla.","El volumen es exclusivamente geométrico y bruto; no representa una medición neta de material ni una cantidad de compra."]} | {"documentId":"EST-SB-20260710","title":"Planos de estructura de la sala de bombas contra incendios","date":"2026-07-10","sheet":"Estructura A101 / p. 2, Arquitectura A103 / p. 5"} | provisional | ["En bombas, la cabeza de viga sigue el plano de pilares con pendiente del 5 %. En oficinas, se adopta cabeza de viga a +4,200 m bajo la placa; el encuentro con pilares a +5,000 m requiere revisión.","Ejes unidos a centros de pilares o vigas; chapas de unión y longitudes libres sin desarrollar.","Acuerdos de unión entre alma y alas omitidos.","Registro de líneas del PDF general con envolvente de 10,2 × 8,2 m. Estimación de trabajo de implantación de ±0,15 m, pendiente de CAD nativo; no constituye una precisión topográfica garantizada."] | {"horizontalStatus":"derivado","verticalStatus":"provisional","baseElevationM":286.25,"note":"Registro de líneas del PDF general con envolvente de 10,2 × 8,2 m. Estimación de trabajo de implantación de ±0,15 m, pendiente de CAD nativo; no constituye una precisión topográfica garantizada."} | {"boundingBoxM":{"min":[13.115467,26.419959,5.362812],"max":[14.338533,33.902041,6.237188]},"extentsM":[1.223066,7.482082,0.874376],"meshSurfaceM2":13.386011,"meshVolumeM3":0.083907,"closedSolid":true,"basis":"Geometría triangulada releída del IFC; envolventes y magnitudes no contractuales."} | {"material":true,"document":true,"quantities":true,"containerGuid":"0Wh59pm9LO_einrwiq6Es1","containerName":"Planta baja"} | {"id":"structure","name":"Estructura"} | {"profileId":"steel_structural","name":"Acero estructural · protección gris","materialName":"Acero estructural S355JR","physicalMaterialStatus":"known","physicalMaterialSource":"EST-SB-20260710 · Estructura A101 / p. 2, Arquitectura A103 / p. 5","appearanceStatus":"criterio_visual","appearanceBasis":"S355JR consta en la documentación; protección superficial gris adoptada para visualización, sin especificación de pintura confirmada.","note":"La apariencia gráfica no modifica ni confirma la especificación física del material."} | {"elementId":"pump_house_0056","ifcGuid":"32QLW3jHDKkOgxNl6AP4OS","ifcClass":"IfcBeam","buildingId":"pump_house","buildingName":"Sala de bombas contra incendios","sourceDocumentId":"EST-SB-20260710","sourceRepresentationKind":"documentary_mesh"} | {"layerId":"structure","layerName":"Estructura","role":"Viga","basis":"Clasificación por función del elemento; no modifica las especificaciones documentales."} | structure | {"profileId":"steel_structural","name":"Acero estructural · protección gris","status":"criterio_visual","basis":"S355JR consta en la documentación; protección superficial gris adoptada para visualización, sin especificación de pintura confirmada.","physicalMaterialUnchanged":true} | EST-SB-20260710 · Estructura A101 / p. 2, Arquitectura A103 / p. 5 | Perfil y dimensiones XY documentados o deducidos; cota de viga deducida de la cabeza de pilar o del intradós de la placa prefabricada. | IPE500 | https://sections.arcelormittal.com/repository2/Sections/5_1_5_ArcelorMittal_FR_EN_RU_web.pdf | 76 | Acuerdos de unión entre alma y alas omitidos. | Ejes unidos a centros de pilares o vigas; chapas de unión y longitudes libres sin desarrollar. | En bombas, la cabeza de viga sigue el plano de pilares con pendiente del 5 %. En oficinas, se adopta cabeza de viga a +4,200 m bajo la placa; el encuentro con pilares a +5,000 m requiere revisión. | Registro de líneas del PDF general con envolvente de 10,2 × 8,2 m. Estimación de trabajo de implantación de ±0,15 m, pendiente de CAD nativo; no constituye una precisión topográfica garantizada. | Estructura | EST-SB-20260710 · Estructura A101 / p. 2, Arquitectura A103 / p. 5 | 286.25 | Estructura | Acero estructural · protección gris | 500 | 200 | 10.2 | 16 | steel_structural | [0.396078,0.454902,0.482353] | 0.52 | 0.35 | S355JR consta en la documentación; protección superficial gris adoptada para visualización, sin especificación de pintura confirmada. | Estructura; BIM · Estructura
Sala de bombas contra incendios · viga de atado VC1 · 1 | Planos de estructura de la sala de bombas contra incendios | Hormigón armado HA-30 | 9.5 × 0.25 × 0.6 | 284.25 | 284.85 | 1.425 | pump_house_0061 | 9.44552 | 1.54161 | 0.6 | 16.45 | 1.425 | pump_house | Sala de bombas contra incendios | {"name":"Hormigón armado HA-30","source":"EST-SB-20260710 · Estructura A201 / p. 4; nota de resistencia de zapatas y vigas de atado","status":"known"} | {"documented":[{"label":"Cota superior absoluta","value":284.85,"unit":"m","source":"EST-SB-20260710 · Estructura A201 / p. 4","status":"documentado"},{"label":"Anchura","value":0.25,"unit":"m","source":"EST-SB-20260710 · Estructura A201 / p. 4","status":"documentado"},{"label":"Altura de sección","value":0.6,"unit":"m","source":"EST-SB-20260710 · Estructura A201 / p. 4","status":"documentado"}],"geometry":[{"label":"Dimensiones de la caja local del elemento (X, Y, Z)","value":"9.5 × 0.25 × 0.6","unit":"m","source":"Malla triangulada del elemento en ejes locales del edificio","status":"derivado"},{"label":"Cota mínima absoluta de la malla","value":284.25,"unit":"m","source":"Malla de proyecto y origen altimétrico 285 m","status":"derivado"},{"label":"Cota máxima absoluta de la malla","value":284.85,"unit":"m","source":"Malla de proyecto y origen altimétrico 285 m","status":"derivado"},{"label":"Volumen geométrico bruto","value":1.425,"unit":"m³","source":"Malla cerrada del elemento","status":"derivado"}],"notes":["Las dimensiones documentadas proceden de anotaciones o cuadros; la caja y el volumen se calculan a partir de la malla.","El volumen es exclusivamente geométrico y bruto; no representa una medición neta de material ni una cantidad de compra."]} | {"documentId":"EST-SB-20260710","title":"Planos de estructura de la sala de bombas contra incendios","date":"2026-07-10","sheet":"Estructura A201 / p. 4"} | provisional | ["Las secciones también indican 284,75 m en la zona de zócalo y viga, frente a 284,85 m en la nota general. Ambas cotas requieren conciliación.","Excentricidad de las vigas de atado respecto a los muros simplificada mediante ejes; armaduras no modeladas.","Registro de líneas del PDF general con envolvente de 10,2 × 8,2 m. Estimación de trabajo de implantación de ±0,15 m, pendiente de CAD nativo; no constituye una precisión topográfica garantizada."] | {"horizontalStatus":"derivado","verticalStatus":"provisional","baseElevationM":286.25,"note":"Registro de líneas del PDF general con envolvente de 10,2 × 8,2 m. Estimación de trabajo de implantación de ±0,15 m, pendiente de CAD nativo; no constituye una precisión topográfica garantizada."} | {"boundingBoxM":{"min":[8.493476,25.675143,-0.75],"max":[17.938995,27.216751,-0.15]},"extentsM":[9.445519,1.541608,0.6],"meshSurfaceM2":16.450006,"meshVolumeM3":1.425002,"closedSolid":true,"basis":"Geometría triangulada releída del IFC; envolventes y magnitudes no contractuales."} | {"material":true,"document":true,"quantities":true,"containerGuid":"0Wh59pm9LO_einrwiq6Es1","containerName":"Planta baja"} | {"id":"foundations","name":"Cimentaciones"} | {"profileId":"concrete_ha30","name":"Hormigón HA-30","materialName":"Hormigón armado HA-30","physicalMaterialStatus":"known","physicalMaterialSource":"EST-SB-20260710 · Estructura A201 / p. 4; nota de resistencia de zapatas y vigas de atado","appearanceStatus":"criterio_visual","appearanceBasis":"Interpretación visual del material documental; el acabado, tono y parámetros PBR no son una especificación contractual.","note":"La apariencia gráfica no modifica ni confirma la especificación física del material."} | {"elementId":"pump_house_0061","ifcGuid":"2zElhL8YjJ0P2kUEvZKeE4","ifcClass":"IfcBeam","buildingId":"pump_house","buildingName":"Sala de bombas contra incendios","sourceDocumentId":"EST-SB-20260710","sourceRepresentationKind":"documentary_mesh"} | {"layerId":"foundations","layerName":"Cimentaciones","role":"Viga","basis":"Clasificación por función del elemento; no modifica las especificaciones documentales."} | foundations | {"profileId":"concrete_ha30","name":"Hormigón HA-30","status":"criterio_visual","basis":"Interpretación visual del material documental; el acabado, tono y parámetros PBR no son una especificación contractual.","physicalMaterialUnchanged":true} | EST-SB-20260710 · Estructura A201 / p. 4 | Sección y cota superior documentadas en el cuadro y las notas generales; trazado simplificado uniendo los centros de las zapatas. |  |  |  |  |  |  | Registro de líneas del PDF general con envolvente de 10,2 × 8,2 m. Estimación de trabajo de implantación de ±0,15 m, pendiente de CAD nativo; no constituye una precisión topográfica garantizada. | Cimentación | EST-SB-20260710 · Estructura A201 / p. 4; nota de resistencia de zapatas y vigas de atado | 286.25 | Cimentaciones | Hormigón HA-30 |  |  |  |  | concrete_ha30 | [0.658824,0.658824,0.623529] | 0.94 | 0 | Interpretación visual del material documental; el acabado, tono y parámetros PBR no son una especificación contractual. | Cimentación; BIM · Cimentaciones | JH_Trazabilidad - Anchura (m): 0.25; Altura de sección (m): 0.6; Cota superior absoluta (m): 284.85; Simplificación geométrica: Excentricidad de las vigas de atado respecto a los muros simplificada mediante ejes; armaduras no modeladas.; Discrepancia pendiente: Las secciones también indican 284,75 m en la zona de zócalo y viga, frente a 284,85 m en la nota general. Ambas cotas requieren conciliación.; JH_DimensionesDocumentadas - Cota superior absoluta: 284.85 m; Anchura: 0.25 m; Altura de sección: 0.6 m
Sala de bombas contra incendios · viga de atado VC1 · 2 | Planos de estructura de la sala de bombas contra incendios | Hormigón armado HA-30 | 9.5 × 0.25 × 0.6 | 284.25 | 284.85 | 1.425 | pump_house_0062 | 9.44552 | 1.54161 | 0.6 | 16.45 | 1.425 | pump_house | Sala de bombas contra incendios | {"name":"Hormigón armado HA-30","source":"EST-SB-20260710 · Estructura A201 / p. 4; nota de resistencia de zapatas y vigas de atado","status":"known"} | {"documented":[{"label":"Cota superior absoluta","value":284.85,"unit":"m","source":"EST-SB-20260710 · Estructura A201 / p. 4","status":"documentado"},{"label":"Anchura","value":0.25,"unit":"m","source":"EST-SB-20260710 · Estructura A201 / p. 4","status":"documentado"},{"label":"Altura de sección","value":0.6,"unit":"m","source":"EST-SB-20260710 · Estructura A201 / p. 4","status":"documentado"}],"geometry":[{"label":"Dimensiones de la caja local del elemento (X, Y, Z)","value":"9.5 × 0.25 × 0.6","unit":"m","source":"Malla triangulada del elemento en ejes locales del edificio","status":"derivado"},{"label":"Cota mínima absoluta de la malla","value":284.25,"unit":"m","source":"Malla de proyecto y origen altimétrico 285 m","status":"derivado"},{"label":"Cota máxima absoluta de la malla","value":284.85,"unit":"m","source":"Malla de proyecto y origen altimétrico 285 m","status":"derivado"},{"label":"Volumen geométrico bruto","value":1.425,"unit":"m³","source":"Malla cerrada del elemento","status":"derivado"}],"notes":["Las dimensiones documentadas proceden de anotaciones o cuadros; la caja y el volumen se calculan a partir de la malla.","El volumen es exclusivamente geométrico y bruto; no representa una medición neta de material ni una cantidad de compra."]} | {"documentId":"EST-SB-20260710","title":"Planos de estructura de la sala de bombas contra incendios","date":"2026-07-10","sheet":"Estructura A201 / p. 4"} | provisional | ["Las secciones también indican 284,75 m en la zona de zócalo y viga, frente a 284,85 m en la nota general. Ambas cotas requieren conciliación.","Excentricidad de las vigas de atado respecto a los muros simplificada mediante ejes; armaduras no modeladas.","Registro de líneas del PDF general con envolvente de 10,2 × 8,2 m. Estimación de trabajo de implantación de ±0,15 m, pendiente de CAD nativo; no constituye una precisión topográfica garantizada."] | {"horizontalStatus":"derivado","verticalStatus":"provisional","baseElevationM":286.25,"note":"Registro de líneas del PDF general con envolvente de 10,2 × 8,2 m. Estimación de trabajo de implantación de ±0,15 m, pendiente de CAD nativo; no constituye una precisión topográfica garantizada."} | {"boundingBoxM":{"min":[9.515005,33.105249,-0.75],"max":[18.960524,34.646857,-0.15]},"extentsM":[9.445519,1.541608,0.6],"meshSurfaceM2":16.450006,"meshVolumeM3":1.425002,"closedSolid":true,"basis":"Geometría triangulada releída del IFC; envolventes y magnitudes no contractuales."} | {"material":true,"document":true,"quantities":true,"containerGuid":"0Wh59pm9LO_einrwiq6Es1","containerName":"Planta baja"} | {"id":"foundations","name":"Cimentaciones"} | {"profileId":"concrete_ha30","name":"Hormigón HA-30","materialName":"Hormigón armado HA-30","physicalMaterialStatus":"known","physicalMaterialSource":"EST-SB-20260710 · Estructura A201 / p. 4; nota de resistencia de zapatas y vigas de atado","appearanceStatus":"criterio_visual","appearanceBasis":"Interpretación visual del material documental; el acabado, tono y parámetros PBR no son una especificación contractual.","note":"La apariencia gráfica no modifica ni confirma la especificación física del material."} | {"elementId":"pump_house_0062","ifcGuid":"1nY1XS4ZnLvg2RMjhi2XLx","ifcClass":"IfcBeam","buildingId":"pump_house","buildingName":"Sala de bombas contra incendios","sourceDocumentId":"EST-SB-20260710","sourceRepresentationKind":"documentary_mesh"} | {"layerId":"foundations","layerName":"Cimentaciones","role":"Viga","basis":"Clasificación por función del elemento; no modifica las especificaciones documentales."} | foundations | {"profileId":"concrete_ha30","name":"Hormigón HA-30","status":"criterio_visual","basis":"Interpretación visual del material documental; el acabado, tono y parámetros PBR no son una especificación contractual.","physicalMaterialUnchanged":true} | EST-SB-20260710 · Estructura A201 / p. 4 | Sección y cota superior documentadas en el cuadro y las notas generales; trazado simplificado uniendo los centros de las zapatas. |  |  |  |  |  |  | Registro de líneas del PDF general con envolvente de 10,2 × 8,2 m. Estimación de trabajo de implantación de ±0,15 m, pendiente de CAD nativo; no constituye una precisión topográfica garantizada. | Cimentación | EST-SB-20260710 · Estructura A201 / p. 4; nota de resistencia de zapatas y vigas de atado | 286.25 | Cimentaciones | Hormigón HA-30 |  |  |  |  | concrete_ha30 | [0.658824,0.658824,0.623529] | 0.94 | 0 | Interpretación visual del material documental; el acabado, tono y parámetros PBR no son una especificación contractual. | Cimentación; BIM · Cimentaciones | JH_Trazabilidad - Anchura (m): 0.25; Altura de sección (m): 0.6; Cota superior absoluta (m): 284.85; Simplificación geométrica: Excentricidad de las vigas de atado respecto a los muros simplificada mediante ejes; armaduras no modeladas.; Discrepancia pendiente: Las secciones también indican 284,75 m en la zona de zócalo y viga, frente a 284,85 m en la nota general. Ambas cotas requieren conciliación.; JH_DimensionesDocumentadas - Cota superior absoluta: 284.85 m; Anchura: 0.25 m; Altura de sección: 0.6 m
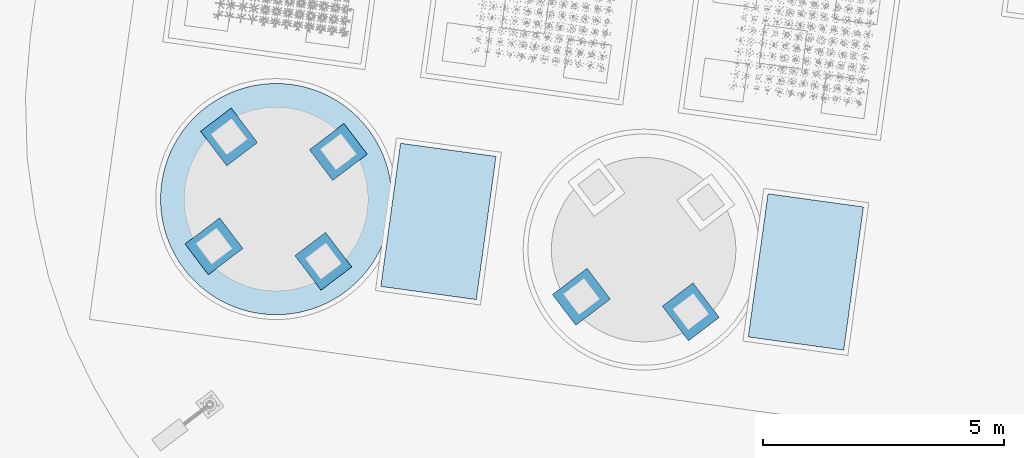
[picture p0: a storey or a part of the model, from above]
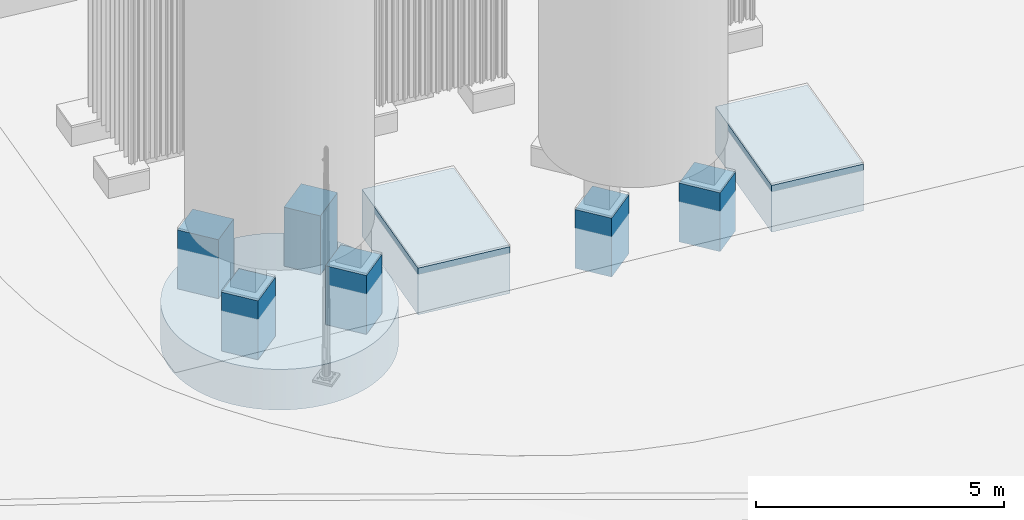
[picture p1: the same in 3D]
Properties of the parts of a building model (IFC4), part 2 of 134

# IfcBeam (24)
Name | Document | Material = JH_Trazabilidad, Material = name | Dimensiones de la caja local del elemento (X, Y, Z) | Cota mínima absoluta de la malla (m) | Cota máxima absoluta de la malla (m) | Volumen geométrico bruto (m3) = Volumen geométrico (m³) | Reference = Identificador del elemento = Identificador | ExtensionX (m) | ExtensionY (m) | ExtensionZ (m) | SuperficieDeLaMalla (m2) | VolumenGeometrico (m3) = GrossVolume (m3) | buildingId | buildingName = Edificio | material | dimensions | JH_InformacionBIM, source = DocumentoFuente | status = EstadoDeInformacion | issues = IncidenciasPendientes | positioning = PosicionYEstado | geometryMetrics | ifcAssociations | visualLayer | materialAppearance | visualizationIdentity | classification | layerId = IdentificadorCapa | appearance | Planos de referencia | Base geométrica | Perfil laminado = JH_DimensionesDocumentadas, Perfil | Catálogo del perfil | Página PDF del catálogo | Acuerdos del perfil | Extremos y uniones | Coordinación de cotas pendiente | Estado de la implantación | Disciplina | Referencia del material = JH_EvidenciaDeMaterial, source | Cota de planta baja terminada (m) | Capa BIM = NombreCapa | Acabado de visualización = Acabado | Canto nominal del perfil | Anchura nominal de ala | Espesor nominal de alma | Espesor nominal de ala | JH_AcabadoVisual, Perfil | ColorRGB | Rugosidad | Metallicidad | Referencia | Group | Discrepancia entre versiones
Sala de bombas contra incendios · viga de atado VC1 · 3 | Planos de estructura de la sala de bombas contra incendios | Hormigón armado HA-30 | 0.25 × 7.5 × 0.6 | 284.25 | 284.85 | 1.125 | pump_house_0063 | 1.2692 | 7.46416 | 0.6 | 13.05 | 1.125 | pump_house | Sala de bombas contra incendios | {"name":"Hormigón armado HA-30","source":"EST-SB-20260710 · Estructura A201 / p. 4; nota de resistencia de zapatas y vigas de atado","status":"known"} | {"documented":[{"label":"Cota superior absoluta","value":284.85,"unit":"m","source":"EST-SB-20260710 · Estructura A201 / p. 4","status":"documentado"},{"label":"Anchura","value":0.25,"unit":"m","source":"EST-SB-20260710 · Estructura A201 / p. 4","status":"documentado"},{"label":"Altura de sección","value":0.6,"unit":"m","source":"EST-SB-20260710 · Estructura A201 / p. 4","status":"documentado"}],"geometry":[{"label":"Dimensiones de la caja local del elemento (X, Y, Z)","value":"0.25 × 7.5 × 0.6","unit":"m","source":"Malla triangulada del elemento en ejes locales del edificio","status":"derivado"},{"label":"Cota mínima absoluta de la malla","value":284.25,"unit":"m","source":"Malla de proyecto y origen altimétrico 285 m","status":"derivado"},{"label":"Cota máxima absoluta de la malla","value":284.85,"unit":"m","source":"Malla de proyecto y origen altimétrico 285 m","status":"derivado"},{"label":"Volumen geométrico bruto","value":1.125,"unit":"m³","source":"Malla cerrada del elemento","status":"derivado"}],"notes":["Las dimensiones documentadas proceden de anotaciones o cuadros; la caja y el volumen se calculan a partir de la malla.","El volumen es exclusivamente geométrico y bruto; no representa una medición neta de material ni una cantidad de compra."]} | {"documentId":"EST-SB-20260710","title":"Planos de estructura de la sala de bombas contra incendios","date":"2026-07-10","sheet":"Estructura A201 / p. 4"} | provisional | ["Las secciones también indican 284,75 m en la zona de zócalo y viga, frente a 284,85 m en la nota general. Ambas cotas requieren conciliación.","Excentricidad de las vigas de atado respecto a los muros simplificada mediante ejes; armaduras no modeladas.","Registro de líneas del PDF general con envolvente de 10,2 × 8,2 m. Estimación de trabajo de implantación de ±0,15 m, pendiente de CAD nativo; no constituye una precisión topográfica garantizada."] | {"horizontalStatus":"derivado","verticalStatus":"provisional","baseElevationM":286.25,"note":"Registro de líneas del PDF general con envolvente de 10,2 × 8,2 m. Estimación de trabajo de implantación de ±0,15 m, pendiente de CAD nativo; no constituye una precisión topográfica garantizada."} | {"boundingBoxM":{"min":[8.386666,27.07589,-0.75],"max":[9.655866,34.540047,-0.15]},"extentsM":[1.2692,7.464157,0.6],"meshSurfaceM2":13.049997,"meshVolumeM3":1.124999,"closedSolid":true,"basis":"Geometría triangulada releída del IFC; envolventes y magnitudes no contractuales."} | {"material":true,"document":true,"quantities":true,"containerGuid":"0Wh59pm9LO_einrwiq6Es1","containerName":"Planta baja"} | {"id":"foundations","name":"Cimentaciones"} | {"profileId":"concrete_ha30","name":"Hormigón HA-30","materialName":"Hormigón armado HA-30","physicalMaterialStatus":"known","physicalMaterialSource":"EST-SB-20260710 · Estructura A201 / p. 4; nota de resistencia de zapatas y vigas de atado","appearanceStatus":"criterio_visual","appearanceBasis":"Interpretación visual del material documental; el acabado, tono y parámetros PBR no son una especificación contractual.","note":"La apariencia gráfica no modifica ni confirma la especificación física del material."} | {"elementId":"pump_house_0063","ifcGuid":"1GSAPBLqbGiB$uIaW13dxC","ifcClass":"IfcBeam","buildingId":"pump_house","buildingName":"Sala de bombas contra incendios","sourceDocumentId":"EST-SB-20260710","sourceRepresentationKind":"documentary_mesh"} | {"layerId":"foundations","layerName":"Cimentaciones","role":"Viga","basis":"Clasificación por función del elemento; no modifica las especificaciones documentales."} | foundations | {"profileId":"concrete_ha30","name":"Hormigón HA-30","status":"criterio_visual","basis":"Interpretación visual del material documental; el acabado, tono y parámetros PBR no son una especificación contractual.","physicalMaterialUnchanged":true} | EST-SB-20260710 · Estructura A201 / p. 4 | Sección y cota superior documentadas en el cuadro y las notas generales; trazado simplificado uniendo los centros de las zapatas. |  |  |  |  |  |  | Registro de líneas del PDF general con envolvente de 10,2 × 8,2 m. Estimación de trabajo de implantación de ±0,15 m, pendiente de CAD nativo; no constituye una precisión topográfica garantizada. | Cimentación | EST-SB-20260710 · Estructura A201 / p. 4; nota de resistencia de zapatas y vigas de atado | 286.25 | Cimentaciones | Hormigón HA-30 |  |  |  |  | concrete_ha30 | [0.658824,0.658824,0.623529] | 0.94 | 0 | Interpretación visual del material documental; el acabado, tono y parámetros PBR no son una especificación contractual. | Cimentación; BIM · Cimentaciones | JH_Trazabilidad - Anchura (m): 0.25; Altura de sección (m): 0.6; Cota superior absoluta (m): 284.85; Simplificación geométrica: Excentricidad de las vigas de atado respecto a los muros simplificada mediante ejes; armaduras no modeladas.; Discrepancia pendiente: Las secciones también indican 284,75 m en la zona de zócalo y viga, frente a 284,85 m en la nota general. Ambas cotas requieren conciliación.; JH_DimensionesDocumentadas - Cota superior absoluta: 284.85 m; Anchura: 0.25 m; Altura de sección: 0.6 m
Sala de bombas contra incendios · viga de atado VC1 · 4 | Planos de estructura de la sala de bombas contra incendios | Hormigón armado HA-30 | 0.25 × 7.5 × 0.6 | 284.25 | 284.85 | 1.125 | pump_house_0064 | 1.2692 | 7.46416 | 0.6 | 13.05 | 1.125 | pump_house | Sala de bombas contra incendios | {"name":"Hormigón armado HA-30","source":"EST-SB-20260710 · Estructura A201 / p. 4; nota de resistencia de zapatas y vigas de atado","status":"known"} | {"documented":[{"label":"Cota superior absoluta","value":284.85,"unit":"m","source":"EST-SB-20260710 · Estructura A201 / p. 4","status":"documentado"},{"label":"Anchura","value":0.25,"unit":"m","source":"EST-SB-20260710 · Estructura A201 / p. 4","status":"documentado"},{"label":"Altura de sección","value":0.6,"unit":"m","source":"EST-SB-20260710 · Estructura A201 / p. 4","status":"documentado"}],"geometry":[{"label":"Dimensiones de la caja local del elemento (X, Y, Z)","value":"0.25 × 7.5 × 0.6","unit":"m","source":"Malla triangulada del elemento en ejes locales del edificio","status":"derivado"},{"label":"Cota mínima absoluta de la malla","value":284.25,"unit":"m","source":"Malla de proyecto y origen altimétrico 285 m","status":"derivado"},{"label":"Cota máxima absoluta de la malla","value":284.85,"unit":"m","source":"Malla de proyecto y origen altimétrico 285 m","status":"derivado"},{"label":"Volumen geométrico bruto","value":1.125,"unit":"m³","source":"Malla cerrada del elemento","status":"derivado"}],"notes":["Las dimensiones documentadas proceden de anotaciones o cuadros; la caja y el volumen se calculan a partir de la malla.","El volumen es exclusivamente geométrico y bruto; no representa una medición neta de material ni una cantidad de compra."]} | {"documentId":"EST-SB-20260710","title":"Planos de estructura de la sala de bombas contra incendios","date":"2026-07-10","sheet":"Estructura A201 / p. 4"} | provisional | ["Las secciones también indican 284,75 m en la zona de zócalo y viga, frente a 284,85 m en la nota general. Ambas cotas requieren conciliación.","Excentricidad de las vigas de atado respecto a los muros simplificada mediante ejes; armaduras no modeladas.","Registro de líneas del PDF general con envolvente de 10,2 × 8,2 m. Estimación de trabajo de implantación de ±0,15 m, pendiente de CAD nativo; no constituye una precisión topográfica garantizada."] | {"horizontalStatus":"derivado","verticalStatus":"provisional","baseElevationM":286.25,"note":"Registro de líneas del PDF general con envolvente de 10,2 × 8,2 m. Estimación de trabajo de implantación de ±0,15 m, pendiente de CAD nativo; no constituye una precisión topográfica garantizada."} | {"boundingBoxM":{"min":[17.798134,25.781953,-0.75],"max":[19.067334,33.24611,-0.15]},"extentsM":[1.2692,7.464157,0.6],"meshSurfaceM2":13.049997,"meshVolumeM3":1.124999,"closedSolid":true,"basis":"Geometría triangulada releída del IFC; envolventes y magnitudes no contractuales."} | {"material":true,"document":true,"quantities":true,"containerGuid":"0Wh59pm9LO_einrwiq6Es1","containerName":"Planta baja"} | {"id":"foundations","name":"Cimentaciones"} | {"profileId":"concrete_ha30","name":"Hormigón HA-30","materialName":"Hormigón armado HA-30","physicalMaterialStatus":"known","physicalMaterialSource":"EST-SB-20260710 · Estructura A201 / p. 4; nota de resistencia de zapatas y vigas de atado","appearanceStatus":"criterio_visual","appearanceBasis":"Interpretación visual del material documental; el acabado, tono y parámetros PBR no son una especificación contractual.","note":"La apariencia gráfica no modifica ni confirma la especificación física del material."} | {"elementId":"pump_house_0064","ifcGuid":"2rtl0TQ1DGIgasBMAtu7Xo","ifcClass":"IfcBeam","buildingId":"pump_house","buildingName":"Sala de bombas contra incendios","sourceDocumentId":"EST-SB-20260710","sourceRepresentationKind":"documentary_mesh"} | {"layerId":"foundations","layerName":"Cimentaciones","role":"Viga","basis":"Clasificación por función del elemento; no modifica las especificaciones documentales."} | foundations | {"profileId":"concrete_ha30","name":"Hormigón HA-30","status":"criterio_visual","basis":"Interpretación visual del material documental; el acabado, tono y parámetros PBR no son una especificación contractual.","physicalMaterialUnchanged":true} | EST-SB-20260710 · Estructura A201 / p. 4 | Sección y cota superior documentadas en el cuadro y las notas generales; trazado simplificado uniendo los centros de las zapatas. |  |  |  |  |  |  | Registro de líneas del PDF general con envolvente de 10,2 × 8,2 m. Estimación de trabajo de implantación de ±0,15 m, pendiente de CAD nativo; no constituye una precisión topográfica garantizada. | Cimentación | EST-SB-20260710 · Estructura A201 / p. 4; nota de resistencia de zapatas y vigas de atado | 286.25 | Cimentaciones | Hormigón HA-30 |  |  |  |  | concrete_ha30 | [0.658824,0.658824,0.623529] | 0.94 | 0 | Interpretación visual del material documental; el acabado, tono y parámetros PBR no son una especificación contractual. | Cimentación; BIM · Cimentaciones | JH_Trazabilidad - Anchura (m): 0.25; Altura de sección (m): 0.6; Cota superior absoluta (m): 284.85; Simplificación geométrica: Excentricidad de las vigas de atado respecto a los muros simplificada mediante ejes; armaduras no modeladas.; Discrepancia pendiente: Las secciones también indican 284,75 m en la zona de zócalo y viga, frente a 284,85 m en la nota general. Ambas cotas requieren conciliación.; JH_DimensionesDocumentadas - Cota superior absoluta: 284.85 m; Anchura: 0.25 m; Altura de sección: 0.6 m
Edificio de oficinas · viga de cubierta HEA600 · 1 | Planos de estructura del edificio de oficinas; Planos de estructura del edificio de oficinas | Acero estructural S355JR | 9.65 × 0.3 × 0.59 | 289.56 | 290.15 | 0.212493 | office_0245 | 1.61157 | 9.60093 | 0.59 | 22.7601 | 0.212493 | office | Edificio de oficinas | {"name":"Acero estructural S355JR","source":"EST-OF-20260710 · Estructura B102 / p. 3, B103 / p. 4","status":"known"} | {"documented":[{"label":"Perfil","value":"HEA600","unit":"designación","source":"EST-OF-20260710 · Estructura B102 / p. 3, B103 / p. 4","status":"documentado"},{"label":"Canto nominal del perfil","value":590,"unit":"mm","source":"Catálogo de perfiles ArcelorMittal · 86","status":"documentado"},{"label":"Anchura nominal de ala","value":300,"unit":"mm","source":"Catálogo de perfiles ArcelorMittal · 86","status":"documentado"},{"label":"Espesor nominal de alma","value":13,"unit":"mm","source":"Catálogo de perfiles ArcelorMittal · 86","status":"documentado"},{"label":"Espesor nominal de ala","value":25,"unit":"mm","source":"Catálogo de perfiles ArcelorMittal · 86","status":"documentado"}],"geometry":[{"label":"Dimensiones de la caja local del elemento (X, Y, Z)","value":"9.65 × 0.3 × 0.59","unit":"m","source":"Malla triangulada del elemento en ejes locales del edificio","status":"derivado"},{"label":"Cota mínima absoluta de la malla","value":289.56,"unit":"m","source":"Malla de proyecto y origen altimétrico 285 m","status":"derivado"},{"label":"Cota máxima absoluta de la malla","value":290.15,"unit":"m","source":"Malla de proyecto y origen altimétrico 285 m","status":"derivado"},{"label":"Volumen geométrico bruto","value":0.212493,"unit":"m³","source":"Malla cerrada del elemento","status":"derivado"}],"notes":["Las dimensiones documentadas proceden de anotaciones o cuadros; la caja y el volumen se calculan a partir de la malla.","El volumen es exclusivamente geométrico y bruto; no representa una medición neta de material ni una cantidad de compra."]} | {"documentId":"EST-OF-20260710","title":"Planos de estructura del edificio de oficinas","date":"2026-07-10","sheet":"Estructura B102 / p. 3, B103 / p. 4"} | provisional | ["En bombas, la cabeza de viga sigue el plano de pilares con pendiente del 5 %. En oficinas, se adopta cabeza de viga a +4,200 m bajo la placa; el encuentro con pilares a +5,000 m requiere revisión.","El plano general de 2026-07-31 mantiene el edificio de oficinas de 200 m², mientras documentación anterior indica su supresión. Se conserva lo dibujado, pendiente de confirmación de la propiedad y del equipo de diseño.","Ejes unidos a centros de pilares o vigas; chapas de unión y longitudes libres sin desarrollar.","Acuerdos de unión entre alma y alas omitidos.","Registro de líneas del PDF general, envolvente de 20 × 10 m; eje local 1 al norte y acceso del lado A al oeste. Estimación de trabajo de implantación de ±0,15 m, pendiente de CAD; no constituye una precisión topográfica garantizada."] | {"horizontalStatus":"derivado","verticalStatus":"provisional","baseElevationM":285.95,"note":"Registro de líneas del PDF general, envolvente de 20 × 10 m; eje local 1 al norte y acceso del lado A al oeste. Estimación de trabajo de implantación de ±0,15 m, pendiente de CAD; no constituye una precisión topográfica garantizada."} | {"boundingBoxM":{"min":[16.423313,82.936788,4.56],"max":[18.034885,92.53772,5.15]},"extentsM":[1.611572,9.600932,0.59],"meshSurfaceM2":22.760134,"meshVolumeM3":0.212493,"closedSolid":true,"basis":"Geometría triangulada releída del IFC; envolventes y magnitudes no contractuales."} | {"material":true,"document":true,"quantities":true,"containerGuid":"3ztlotcerHPueDgxP84R6z","containerName":"Planta baja"} | {"id":"structure","name":"Estructura"} | {"profileId":"steel_structural","name":"Acero estructural · protección gris","materialName":"Acero estructural S355JR","physicalMaterialStatus":"known","physicalMaterialSource":"EST-OF-20260710 · Estructura B102 / p. 3, B103 / p. 4","appearanceStatus":"criterio_visual","appearanceBasis":"S355JR consta en la documentación; protección superficial gris adoptada para visualización, sin especificación de pintura confirmada.","note":"La apariencia gráfica no modifica ni confirma la especificación física del material."} | {"elementId":"office_0245","ifcGuid":"1KL_OP6TvKoQOMUgJBUFuK","ifcClass":"IfcBeam","buildingId":"office","buildingName":"Edificio de oficinas","sourceDocumentId":"EST-OF-20260710","sourceRepresentationKind":"documentary_mesh"} | {"layerId":"structure","layerName":"Estructura","role":"Viga","basis":"Clasificación por función del elemento; no modifica las especificaciones documentales."} | structure | {"profileId":"steel_structural","name":"Acero estructural · protección gris","status":"criterio_visual","basis":"S355JR consta en la documentación; protección superficial gris adoptada para visualización, sin especificación de pintura confirmada.","physicalMaterialUnchanged":true} | EST-OF-20260710 · Estructura B102 / p. 3, B103 / p. 4 | Perfil y dimensiones XY documentados o deducidos; cota de viga deducida de la cabeza de pilar o del intradós de la placa prefabricada. | HEA600 | https://sections.arcelormittal.com/repository2/Sections/5_1_5_ArcelorMittal_FR_EN_RU_web.pdf | 86 | Acuerdos de unión entre alma y alas omitidos. | Ejes unidos a centros de pilares o vigas; chapas de unión y longitudes libres sin desarrollar. | En bombas, la cabeza de viga sigue el plano de pilares con pendiente del 5 %. En oficinas, se adopta cabeza de viga a +4,200 m bajo la placa; el encuentro con pilares a +5,000 m requiere revisión. | Registro de líneas del PDF general, envolvente de 20 × 10 m; eje local 1 al norte y acceso del lado A al oeste. Estimación de trabajo de implantación de ±0,15 m, pendiente de CAD; no constituye una precisión topográfica garantizada. | Estructura | EST-OF-20260710 · Estructura B102 / p. 3, B103 / p. 4 | 285.95 | Estructura | Acero estructural · protección gris | 590 | 300 | 13 | 25 | steel_structural | [0.396078,0.454902,0.482353] | 0.52 | 0.35 | S355JR consta en la documentación; protección superficial gris adoptada para visualización, sin especificación de pintura confirmada. | Estructura; BIM · Estructura | El plano general de 2026-07-31 mantiene el edificio de oficinas de 200 m², mientras documentación anterior indica su supresión. Se conserva lo dibujado, pendiente de confirmación de la propiedad y del equipo de diseño.
Edificio de oficinas · viga de cubierta HEA600 · 2 | Planos de estructura del edificio de oficinas; Planos de estructura del edificio de oficinas | Acero estructural S355JR | 9.65 × 0.3 × 0.59 | 289.56 | 290.15 | 0.212493 | office_0246 | 1.61157 | 9.60093 | 0.59 | 22.7601 | 0.212491 | office | Edificio de oficinas | {"name":"Acero estructural S355JR","source":"EST-OF-20260710 · Estructura B102 / p. 3, B103 / p. 4","status":"known"} | {"documented":[{"label":"Perfil","value":"HEA600","unit":"designación","source":"EST-OF-20260710 · Estructura B102 / p. 3, B103 / p. 4","status":"documentado"},{"label":"Canto nominal del perfil","value":590,"unit":"mm","source":"Catálogo de perfiles ArcelorMittal · 86","status":"documentado"},{"label":"Anchura nominal de ala","value":300,"unit":"mm","source":"Catálogo de perfiles ArcelorMittal · 86","status":"documentado"},{"label":"Espesor nominal de alma","value":13,"unit":"mm","source":"Catálogo de perfiles ArcelorMittal · 86","status":"documentado"},{"label":"Espesor nominal de ala","value":25,"unit":"mm","source":"Catálogo de perfiles ArcelorMittal · 86","status":"documentado"}],"geometry":[{"label":"Dimensiones de la caja local del elemento (X, Y, Z)","value":"9.65 × 0.3 × 0.59","unit":"m","source":"Malla triangulada del elemento en ejes locales del edificio","status":"derivado"},{"label":"Cota mínima absoluta de la malla","value":289.56,"unit":"m","source":"Malla de proyecto y origen altimétrico 285 m","status":"derivado"},{"label":"Cota máxima absoluta de la malla","value":290.15,"unit":"m","source":"Malla de proyecto y origen altimétrico 285 m","status":"derivado"},{"label":"Volumen geométrico bruto","value":0.212493,"unit":"m³","source":"Malla cerrada del elemento","status":"derivado"}],"notes":["Las dimensiones documentadas proceden de anotaciones o cuadros; la caja y el volumen se calculan a partir de la malla.","El volumen es exclusivamente geométrico y bruto; no representa una medición neta de material ni una cantidad de compra."]} | {"documentId":"EST-OF-20260710","title":"Planos de estructura del edificio de oficinas","date":"2026-07-10","sheet":"Estructura B102 / p. 3, B103 / p. 4"} | provisional | ["En bombas, la cabeza de viga sigue el plano de pilares con pendiente del 5 %. En oficinas, se adopta cabeza de viga a +4,200 m bajo la placa; el encuentro con pilares a +5,000 m requiere revisión.","El plano general de 2026-07-31 mantiene el edificio de oficinas de 200 m², mientras documentación anterior indica su supresión. Se conserva lo dibujado, pendiente de confirmación de la propiedad y del equipo de diseño.","Ejes unidos a centros de pilares o vigas; chapas de unión y longitudes libres sin desarrollar.","Acuerdos de unión entre alma y alas omitidos.","Registro de líneas del PDF general, envolvente de 20 × 10 m; eje local 1 al norte y acceso del lado A al oeste. Estimación de trabajo de implantación de ±0,15 m, pendiente de CAD; no constituye una precisión topográfica garantizada."] | {"horizontalStatus":"derivado","verticalStatus":"provisional","baseElevationM":285.95,"note":"Registro de líneas del PDF general, envolvente de 20 × 10 m; eje local 1 al norte y acceso del lado A al oeste. Estimación de trabajo de implantación de ±0,15 m, pendiente de CAD; no constituye una precisión topográfica garantizada."} | {"boundingBoxM":{"min":[15.108945,73.376719,4.56],"max":[16.720517,82.97765,5.15]},"extentsM":[1.611572,9.600931,0.59],"meshSurfaceM2":22.76014,"meshVolumeM3":0.212491,"closedSolid":true,"basis":"Geometría triangulada releída del IFC; envolventes y magnitudes no contractuales."} | {"material":true,"document":true,"quantities":true,"containerGuid":"3ztlotcerHPueDgxP84R6z","containerName":"Planta baja"} | {"id":"structure","name":"Estructura"} | {"profileId":"steel_structural","name":"Acero estructural · protección gris","materialName":"Acero estructural S355JR","physicalMaterialStatus":"known","physicalMaterialSource":"EST-OF-20260710 · Estructura B102 / p. 3, B103 / p. 4","appearanceStatus":"criterio_visual","appearanceBasis":"S355JR consta en la documentación; protección superficial gris adoptada para visualización, sin especificación de pintura confirmada.","note":"La apariencia gráfica no modifica ni confirma la especificación física del material."} | {"elementId":"office_0246","ifcGuid":"3f7gCyjS5RiRTQ9i2_T36e","ifcClass":"IfcBeam","buildingId":"office","buildingName":"Edificio de oficinas","sourceDocumentId":"EST-OF-20260710","sourceRepresentationKind":"documentary_mesh"} | {"layerId":"structure","layerName":"Estructura","role":"Viga","basis":"Clasificación por función del elemento; no modifica las especificaciones documentales."} | structure | {"profileId":"steel_structural","name":"Acero estructural · protección gris","status":"criterio_visual","basis":"S355JR consta en la documentación; protección superficial gris adoptada para visualización, sin especificación de pintura confirmada.","physicalMaterialUnchanged":true} | EST-OF-20260710 · Estructura B102 / p. 3, B103 / p. 4 | Perfil y dimensiones XY documentados o deducidos; cota de viga deducida de la cabeza de pilar o del intradós de la placa prefabricada. | HEA600 | https://sections.arcelormittal.com/repository2/Sections/5_1_5_ArcelorMittal_FR_EN_RU_web.pdf | 86 | Acuerdos de unión entre alma y alas omitidos. | Ejes unidos a centros de pilares o vigas; chapas de unión y longitudes libres sin desarrollar. | En bombas, la cabeza de viga sigue el plano de pilares con pendiente del 5 %. En oficinas, se adopta cabeza de viga a +4,200 m bajo la placa; el encuentro con pilares a +5,000 m requiere revisión. | Registro de líneas del PDF general, envolvente de 20 × 10 m; eje local 1 al norte y acceso del lado A al oeste. Estimación de trabajo de implantación de ±0,15 m, pendiente de CAD; no constituye una precisión topográfica garantizada. | Estructura | EST-OF-20260710 · Estructura B102 / p. 3, B103 / p. 4 | 285.95 | Estructura | Acero estructural · protección gris | 590 | 300 | 13 | 25 | steel_structural | [0.396078,0.454902,0.482353] | 0.52 | 0.35 | S355JR consta en la documentación; protección superficial gris adoptada para visualización, sin especificación de pintura confirmada. | Estructura; BIM · Estructura | El plano general de 2026-07-31 mantiene el edificio de oficinas de 200 m², mientras documentación anterior indica su supresión. Se conserva lo dibujado, pendiente de confirmación de la propiedad y del equipo de diseño.
Edificio de oficinas · viga de cubierta HEA600 · 3 | Planos de estructura del edificio de oficinas; Planos de estructura del edificio de oficinas | Acero estructural S355JR | 9.65 × 0.3 × 0.59 | 289.56 | 290.15 | 0.212493 | office_0247 | 1.61157 | 9.60093 | 0.59 | 22.7601 | 0.212491 | office | Edificio de oficinas | {"name":"Acero estructural S355JR","source":"EST-OF-20260710 · Estructura B102 / p. 3, B103 / p. 4","status":"known"} | {"documented":[{"label":"Perfil","value":"HEA600","unit":"designación","source":"EST-OF-20260710 · Estructura B102 / p. 3, B103 / p. 4","status":"documentado"},{"label":"Canto nominal del perfil","value":590,"unit":"mm","source":"Catálogo de perfiles ArcelorMittal · 86","status":"documentado"},{"label":"Anchura nominal de ala","value":300,"unit":"mm","source":"Catálogo de perfiles ArcelorMittal · 86","status":"documentado"},{"label":"Espesor nominal de alma","value":13,"unit":"mm","source":"Catálogo de perfiles ArcelorMittal · 86","status":"documentado"},{"label":"Espesor nominal de ala","value":25,"unit":"mm","source":"Catálogo de perfiles ArcelorMittal · 86","status":"documentado"}],"geometry":[{"label":"Dimensiones de la caja local del elemento (X, Y, Z)","value":"9.65 × 0.3 × 0.59","unit":"m","source":"Malla triangulada del elemento en ejes locales del edificio","status":"derivado"},{"label":"Cota mínima absoluta de la malla","value":289.56,"unit":"m","source":"Malla de proyecto y origen altimétrico 285 m","status":"derivado"},{"label":"Cota máxima absoluta de la malla","value":290.15,"unit":"m","source":"Malla de proyecto y origen altimétrico 285 m","status":"derivado"},{"label":"Volumen geométrico bruto","value":0.212493,"unit":"m³","source":"Malla cerrada del elemento","status":"derivado"}],"notes":["Las dimensiones documentadas proceden de anotaciones o cuadros; la caja y el volumen se calculan a partir de la malla.","El volumen es exclusivamente geométrico y bruto; no representa una medición neta de material ni una cantidad de compra."]} | {"documentId":"EST-OF-20260710","title":"Planos de estructura del edificio de oficinas","date":"2026-07-10","sheet":"Estructura B102 / p. 3, B103 / p. 4"} | provisional | ["En bombas, la cabeza de viga sigue el plano de pilares con pendiente del 5 %. En oficinas, se adopta cabeza de viga a +4,200 m bajo la placa; el encuentro con pilares a +5,000 m requiere revisión.","El plano general de 2026-07-31 mantiene el edificio de oficinas de 200 m², mientras documentación anterior indica su supresión. Se conserva lo dibujado, pendiente de confirmación de la propiedad y del equipo de diseño.","Ejes unidos a centros de pilares o vigas; chapas de unión y longitudes libres sin desarrollar.","Acuerdos de unión entre alma y alas omitidos.","Registro de líneas del PDF general, envolvente de 20 × 10 m; eje local 1 al norte y acceso del lado A al oeste. Estimación de trabajo de implantación de ±0,15 m, pendiente de CAD; no constituye una precisión topográfica garantizada."] | {"horizontalStatus":"derivado","verticalStatus":"provisional","baseElevationM":285.95,"note":"Registro de líneas del PDF general, envolvente de 20 × 10 m; eje local 1 al norte y acceso del lado A al oeste. Estimación de trabajo de implantación de ±0,15 m, pendiente de CAD; no constituye una precisión topográfica garantizada."} | {"boundingBoxM":{"min":[25.547483,81.68235,4.56],"max":[27.159055,91.283281,5.15]},"extentsM":[1.611572,9.600931,0.59],"meshSurfaceM2":22.76014,"meshVolumeM3":0.212491,"closedSolid":true,"basis":"Geometría triangulada releída del IFC; envolventes y magnitudes no contractuales."} | {"material":true,"document":true,"quantities":true,"containerGuid":"3ztlotcerHPueDgxP84R6z","containerName":"Planta baja"} | {"id":"structure","name":"Estructura"} | {"profileId":"steel_structural","name":"Acero estructural · protección gris","materialName":"Acero estructural S355JR","physicalMaterialStatus":"known","physicalMaterialSource":"EST-OF-20260710 · Estructura B102 / p. 3, B103 / p. 4","appearanceStatus":"criterio_visual","appearanceBasis":"S355JR consta en la documentación; protección superficial gris adoptada para visualización, sin especificación de pintura confirmada.","note":"La apariencia gráfica no modifica ni confirma la especificación física del material."} | {"elementId":"office_0247","ifcGuid":"2b1A64kAvOnusH6u1h$0SB","ifcClass":"IfcBeam","buildingId":"office","buildingName":"Edificio de oficinas","sourceDocumentId":"EST-OF-20260710","sourceRepresentationKind":"documentary_mesh"} | {"layerId":"structure","layerName":"Estructura","role":"Viga","basis":"Clasificación por función del elemento; no modifica las especificaciones documentales."} | structure | {"profileId":"steel_structural","name":"Acero estructural · protección gris","status":"criterio_visual","basis":"S355JR consta en la documentación; protección superficial gris adoptada para visualización, sin especificación de pintura confirmada.","physicalMaterialUnchanged":true} | EST-OF-20260710 · Estructura B102 / p. 3, B103 / p. 4 | Perfil y dimensiones XY documentados o deducidos; cota de viga deducida de la cabeza de pilar o del intradós de la placa prefabricada. | HEA600 | https://sections.arcelormittal.com/repository2/Sections/5_1_5_ArcelorMittal_FR_EN_RU_web.pdf | 86 | Acuerdos de unión entre alma y alas omitidos. | Ejes unidos a centros de pilares o vigas; chapas de unión y longitudes libres sin desarrollar. | En bombas, la cabeza de viga sigue el plano de pilares con pendiente del 5 %. En oficinas, se adopta cabeza de viga a +4,200 m bajo la placa; el encuentro con pilares a +5,000 m requiere revisión. | Registro de líneas del PDF general, envolvente de 20 × 10 m; eje local 1 al norte y acceso del lado A al oeste. Estimación de trabajo de implantación de ±0,15 m, pendiente de CAD; no constituye una precisión topográfica garantizada. | Estructura | EST-OF-20260710 · Estructura B102 / p. 3, B103 / p. 4 | 285.95 | Estructura | Acero estructural · protección gris | 590 | 300 | 13 | 25 | steel_structural | [0.396078,0.454902,0.482353] | 0.52 | 0.35 | S355JR consta en la documentación; protección superficial gris adoptada para visualización, sin especificación de pintura confirmada. | Estructura; BIM · Estructura | El plano general de 2026-07-31 mantiene el edificio de oficinas de 200 m², mientras documentación anterior indica su supresión. Se conserva lo dibujado, pendiente de confirmación de la propiedad y del equipo de diseño.
Edificio de oficinas · viga de cubierta HEA600 · 4 | Planos de estructura del edificio de oficinas; Planos de estructura del edificio de oficinas | Acero estructural S355JR | 9.65 × 0.3 × 0.59 | 289.56 | 290.15 | 0.212493 | office_0248 | 1.61157 | 9.60093 | 0.59 | 22.7601 | 0.212493 | office | Edificio de oficinas | {"name":"Acero estructural S355JR","source":"EST-OF-20260710 · Estructura B102 / p. 3, B103 / p. 4","status":"known"} | {"documented":[{"label":"Perfil","value":"HEA600","unit":"designación","source":"EST-OF-20260710 · Estructura B102 / p. 3, B103 / p. 4","status":"documentado"},{"label":"Canto nominal del perfil","value":590,"unit":"mm","source":"Catálogo de perfiles ArcelorMittal · 86","status":"documentado"},{"label":"Anchura nominal de ala","value":300,"unit":"mm","source":"Catálogo de perfiles ArcelorMittal · 86","status":"documentado"},{"label":"Espesor nominal de alma","value":13,"unit":"mm","source":"Catálogo de perfiles ArcelorMittal · 86","status":"documentado"},{"label":"Espesor nominal de ala","value":25,"unit":"mm","source":"Catálogo de perfiles ArcelorMittal · 86","status":"documentado"}],"geometry":[{"label":"Dimensiones de la caja local del elemento (X, Y, Z)","value":"9.65 × 0.3 × 0.59","unit":"m","source":"Malla triangulada del elemento en ejes locales del edificio","status":"derivado"},{"label":"Cota mínima absoluta de la malla","value":289.56,"unit":"m","source":"Malla de proyecto y origen altimétrico 285 m","status":"derivado"},{"label":"Cota máxima absoluta de la malla","value":290.15,"unit":"m","source":"Malla de proyecto y origen altimétrico 285 m","status":"derivado"},{"label":"Volumen geométrico bruto","value":0.212493,"unit":"m³","source":"Malla cerrada del elemento","status":"derivado"}],"notes":["Las dimensiones documentadas proceden de anotaciones o cuadros; la caja y el volumen se calculan a partir de la malla.","El volumen es exclusivamente geométrico y bruto; no representa una medición neta de material ni una cantidad de compra."]} | {"documentId":"EST-OF-20260710","title":"Planos de estructura del edificio de oficinas","date":"2026-07-10","sheet":"Estructura B102 / p. 3, B103 / p. 4"} | provisional | ["En bombas, la cabeza de viga sigue el plano de pilares con pendiente del 5 %. En oficinas, se adopta cabeza de viga a +4,200 m bajo la placa; el encuentro con pilares a +5,000 m requiere revisión.","El plano general de 2026-07-31 mantiene el edificio de oficinas de 200 m², mientras documentación anterior indica su supresión. Se conserva lo dibujado, pendiente de confirmación de la propiedad y del equipo de diseño.","Ejes unidos a centros de pilares o vigas; chapas de unión y longitudes libres sin desarrollar.","Acuerdos de unión entre alma y alas omitidos.","Registro de líneas del PDF general, envolvente de 20 × 10 m; eje local 1 al norte y acceso del lado A al oeste. Estimación de trabajo de implantación de ±0,15 m, pendiente de CAD; no constituye una precisión topográfica garantizada."] | {"horizontalStatus":"derivado","verticalStatus":"provisional","baseElevationM":285.95,"note":"Registro de líneas del PDF general, envolvente de 20 × 10 m; eje local 1 al norte y acceso del lado A al oeste. Estimación de trabajo de implantación de ±0,15 m, pendiente de CAD; no constituye una precisión topográfica garantizada."} | {"boundingBoxM":{"min":[24.233115,72.12228,4.56],"max":[25.844687,81.723212,5.15]},"extentsM":[1.611572,9.600932,0.59],"meshSurfaceM2":22.760134,"meshVolumeM3":0.212493,"closedSolid":true,"basis":"Geometría triangulada releída del IFC; envolventes y magnitudes no contractuales."} | {"material":true,"document":true,"quantities":true,"containerGuid":"3ztlotcerHPueDgxP84R6z","containerName":"Planta baja"} | {"id":"structure","name":"Estructura"} | {"profileId":"steel_structural","name":"Acero estructural · protección gris","materialName":"Acero estructural S355JR","physicalMaterialStatus":"known","physicalMaterialSource":"EST-OF-20260710 · Estructura B102 / p. 3, B103 / p. 4","appearanceStatus":"criterio_visual","appearanceBasis":"S355JR consta en la documentación; protección superficial gris adoptada para visualización, sin especificación de pintura confirmada.","note":"La apariencia gráfica no modifica ni confirma la especificación física del material."} | {"elementId":"office_0248","ifcGuid":"2uraWVgb5Gxwd9gnoUVYSj","ifcClass":"IfcBeam","buildingId":"office","buildingName":"Edificio de oficinas","sourceDocumentId":"EST-OF-20260710","sourceRepresentationKind":"documentary_mesh"} | {"layerId":"structure","layerName":"Estructura","role":"Viga","basis":"Clasificación por función del elemento; no modifica las especificaciones documentales."} | structure | {"profileId":"steel_structural","name":"Acero estructural · protección gris","status":"criterio_visual","basis":"S355JR consta en la documentación; protección superficial gris adoptada para visualización, sin especificación de pintura confirmada.","physicalMaterialUnchanged":true} | EST-OF-20260710 · Estructura B102 / p. 3, B103 / p. 4 | Perfil y dimensiones XY documentados o deducidos; cota de viga deducida de la cabeza de pilar o del intradós de la placa prefabricada. | HEA600 | https://sections.arcelormittal.com/repository2/Sections/5_1_5_ArcelorMittal_FR_EN_RU_web.pdf | 86 | Acuerdos de unión entre alma y alas omitidos. | Ejes unidos a centros de pilares o vigas; chapas de unión y longitudes libres sin desarrollar. | En bombas, la cabeza de viga sigue el plano de pilares con pendiente del 5 %. En oficinas, se adopta cabeza de viga a +4,200 m bajo la placa; el encuentro con pilares a +5,000 m requiere revisión. | Registro de líneas del PDF general, envolvente de 20 × 10 m; eje local 1 al norte y acceso del lado A al oeste. Estimación de trabajo de implantación de ±0,15 m, pendiente de CAD; no constituye una precisión topográfica garantizada. | Estructura | EST-OF-20260710 · Estructura B102 / p. 3, B103 / p. 4 | 285.95 | Estructura | Acero estructural · protección gris | 590 | 300 | 13 | 25 | steel_structural | [0.396078,0.454902,0.482353] | 0.52 | 0.35 | S355JR consta en la documentación; protección superficial gris adoptada para visualización, sin especificación de pintura confirmada. | Estructura; BIM · Estructura | El plano general de 2026-07-31 mantiene el edificio de oficinas de 200 m², mientras documentación anterior indica su supresión. Se conserva lo dibujado, pendiente de confirmación de la propiedad y del equipo de diseño.
Edificio de oficinas · viga de cubierta HEA600 · 5 | Planos de estructura del edificio de oficinas; Planos de estructura del edificio de oficinas | Acero estructural S355JR | 0.3 × 9.21 × 0.59 | 289.56 | 290.15 | 0.202804 | office_0249 | 9.16503 | 1.55164 | 0.59 | 21.7244 | 0.202802 | office | Edificio de oficinas | {"name":"Acero estructural S355JR","source":"EST-OF-20260710 · Estructura B102 / p. 3, B103 / p. 4","status":"known"} | {"documented":[{"label":"Perfil","value":"HEA600","unit":"designación","source":"EST-OF-20260710 · Estructura B102 / p. 3, B103 / p. 4","status":"documentado"},{"label":"Canto nominal del perfil","value":590,"unit":"mm","source":"Catálogo de perfiles ArcelorMittal · 86","status":"documentado"},{"label":"Anchura nominal de ala","value":300,"unit":"mm","source":"Catálogo de perfiles ArcelorMittal · 86","status":"documentado"},{"label":"Espesor nominal de alma","value":13,"unit":"mm","source":"Catálogo de perfiles ArcelorMittal · 86","status":"documentado"},{"label":"Espesor nominal de ala","value":25,"unit":"mm","source":"Catálogo de perfiles ArcelorMittal · 86","status":"documentado"}],"geometry":[{"label":"Dimensiones de la caja local del elemento (X, Y, Z)","value":"0.3 × 9.21 × 0.59","unit":"m","source":"Malla triangulada del elemento en ejes locales del edificio","status":"derivado"},{"label":"Cota mínima absoluta de la malla","value":289.56,"unit":"m","source":"Malla de proyecto y origen altimétrico 285 m","status":"derivado"},{"label":"Cota máxima absoluta de la malla","value":290.15,"unit":"m","source":"Malla de proyecto y origen altimétrico 285 m","status":"derivado"},{"label":"Volumen geométrico bruto","value":0.202804,"unit":"m³","source":"Malla cerrada del elemento","status":"derivado"}],"notes":["Las dimensiones documentadas proceden de anotaciones o cuadros; la caja y el volumen se calculan a partir de la malla.","El volumen es exclusivamente geométrico y bruto; no representa una medición neta de material ni una cantidad de compra."]} | {"documentId":"EST-OF-20260710","title":"Planos de estructura del edificio de oficinas","date":"2026-07-10","sheet":"Estructura B102 / p. 3, B103 / p. 4"} | provisional | ["En bombas, la cabeza de viga sigue el plano de pilares con pendiente del 5 %. En oficinas, se adopta cabeza de viga a +4,200 m bajo la placa; el encuentro con pilares a +5,000 m requiere revisión.","El plano general de 2026-07-31 mantiene el edificio de oficinas de 200 m², mientras documentación anterior indica su supresión. Se conserva lo dibujado, pendiente de confirmación de la propiedad y del equipo de diseño.","Ejes unidos a centros de pilares o vigas; chapas de unión y longitudes libres sin desarrollar.","Acuerdos de unión entre alma y alas omitidos.","Registro de líneas del PDF general, envolvente de 20 × 10 m; eje local 1 al norte y acceso del lado A al oeste. Estimación de trabajo de implantación de ±0,15 m, pendiente de CAD; no constituye una precisión topográfica garantizada."] | {"horizontalStatus":"derivado","verticalStatus":"provisional","baseElevationM":285.95,"note":"Registro de líneas del PDF general, envolvente de 20 × 10 m; eje local 1 al norte y acceso del lado A al oeste. Estimación de trabajo de implantación de ±0,15 m, pendiente de CAD; no constituye una precisión topográfica garantizada."} | {"boundingBoxM":{"min":[17.865852,91.114249,4.56],"max":[27.030884,92.665891,5.15]},"extentsM":[9.165032,1.551642,0.59],"meshSurfaceM2":21.724379,"meshVolumeM3":0.202802,"closedSolid":true,"basis":"Geometría triangulada releída del IFC; envolventes y magnitudes no contractuales."} | {"material":true,"document":true,"quantities":true,"containerGuid":"3ztlotcerHPueDgxP84R6z","containerName":"Planta baja"} | {"id":"structure","name":"Estructura"} | {"profileId":"steel_structural","name":"Acero estructural · protección gris","materialName":"Acero estructural S355JR","physicalMaterialStatus":"known","physicalMaterialSource":"EST-OF-20260710 · Estructura B102 / p. 3, B103 / p. 4","appearanceStatus":"criterio_visual","appearanceBasis":"S355JR consta en la documentación; protección superficial gris adoptada para visualización, sin especificación de pintura confirmada.","note":"La apariencia gráfica no modifica ni confirma la especificación física del material."} | {"elementId":"office_0249","ifcGuid":"38Yd0lAAfUoQkFbkScn6Iw","ifcClass":"IfcBeam","buildingId":"office","buildingName":"Edificio de oficinas","sourceDocumentId":"EST-OF-20260710","sourceRepresentationKind":"documentary_mesh"} | {"layerId":"structure","layerName":"Estructura","role":"Viga","basis":"Clasificación por función del elemento; no modifica las especificaciones documentales."} | structure | {"profileId":"steel_structural","name":"Acero estructural · protección gris","status":"criterio_visual","basis":"S355JR consta en la documentación; protección superficial gris adoptada para visualización, sin especificación de pintura confirmada.","physicalMaterialUnchanged":true} | EST-OF-20260710 · Estructura B102 / p. 3, B103 / p. 4 | Perfil y dimensiones XY documentados o deducidos; cota de viga deducida de la cabeza de pilar o del intradós de la placa prefabricada. | HEA600 | https://sections.arcelormittal.com/repository2/Sections/5_1_5_ArcelorMittal_FR_EN_RU_web.pdf | 86 | Acuerdos de unión entre alma y alas omitidos. | Ejes unidos a centros de pilares o vigas; chapas de unión y longitudes libres sin desarrollar. | En bombas, la cabeza de viga sigue el plano de pilares con pendiente del 5 %. En oficinas, se adopta cabeza de viga a +4,200 m bajo la placa; el encuentro con pilares a +5,000 m requiere revisión. | Registro de líneas del PDF general, envolvente de 20 × 10 m; eje local 1 al norte y acceso del lado A al oeste. Estimación de trabajo de implantación de ±0,15 m, pendiente de CAD; no constituye una precisión topográfica garantizada. | Estructura | EST-OF-20260710 · Estructura B102 / p. 3, B103 / p. 4 | 285.95 | Estructura | Acero estructural · protección gris | 590 | 300 | 13 | 25 | steel_structural | [0.396078,0.454902,0.482353] | 0.52 | 0.35 | S355JR consta en la documentación; protección superficial gris adoptada para visualización, sin especificación de pintura confirmada. | Estructura; BIM · Estructura | El plano general de 2026-07-31 mantiene el edificio de oficinas de 200 m², mientras documentación anterior indica su supresión. Se conserva lo dibujado, pendiente de confirmación de la propiedad y del equipo de diseño.
Edificio de oficinas · viga de cubierta HEA600 · 6 | Planos de estructura del edificio de oficinas; Planos de estructura del edificio de oficinas | Acero estructural S355JR | 0.3 × 9.21 × 0.59 | 289.56 | 290.15 | 0.202804 | office_0250 | 9.16503 | 1.55164 | 0.59 | 21.7244 | 0.202802 | office | Edificio de oficinas | {"name":"Acero estructural S355JR","source":"EST-OF-20260710 · Estructura B102 / p. 3, B103 / p. 4","status":"known"} | {"documented":[{"label":"Perfil","value":"HEA600","unit":"designación","source":"EST-OF-20260710 · Estructura B102 / p. 3, B103 / p. 4","status":"documentado"},{"label":"Canto nominal del perfil","value":590,"unit":"mm","source":"Catálogo de perfiles ArcelorMittal · 86","status":"documentado"},{"label":"Anchura nominal de ala","value":300,"unit":"mm","source":"Catálogo de perfiles ArcelorMittal · 86","status":"documentado"},{"label":"Espesor nominal de alma","value":13,"unit":"mm","source":"Catálogo de perfiles ArcelorMittal · 86","status":"documentado"},{"label":"Espesor nominal de ala","value":25,"unit":"mm","source":"Catálogo de perfiles ArcelorMittal · 86","status":"documentado"}],"geometry":[{"label":"Dimensiones de la caja local del elemento (X, Y, Z)","value":"0.3 × 9.21 × 0.59","unit":"m","source":"Malla triangulada del elemento en ejes locales del edificio","status":"derivado"},{"label":"Cota mínima absoluta de la malla","value":289.56,"unit":"m","source":"Malla de proyecto y origen altimétrico 285 m","status":"derivado"},{"label":"Cota máxima absoluta de la malla","value":290.15,"unit":"m","source":"Malla de proyecto y origen altimétrico 285 m","status":"derivado"},{"label":"Volumen geométrico bruto","value":0.202804,"unit":"m³","source":"Malla cerrada del elemento","status":"derivado"}],"notes":["Las dimensiones documentadas proceden de anotaciones o cuadros; la caja y el volumen se calculan a partir de la malla.","El volumen es exclusivamente geométrico y bruto; no representa una medición neta de material ni una cantidad de compra."]} | {"documentId":"EST-OF-20260710","title":"Planos de estructura del edificio de oficinas","date":"2026-07-10","sheet":"Estructura B102 / p. 3, B103 / p. 4"} | provisional | ["En bombas, la cabeza de viga sigue el plano de pilares con pendiente del 5 %. En oficinas, se adopta cabeza de viga a +4,200 m bajo la placa; el encuentro con pilares a +5,000 m requiere revisión.","El plano general de 2026-07-31 mantiene el edificio de oficinas de 200 m², mientras documentación anterior indica su supresión. Se conserva lo dibujado, pendiente de confirmación de la propiedad y del equipo de diseño.","Ejes unidos a centros de pilares o vigas; chapas de unión y longitudes libres sin desarrollar.","Acuerdos de unión entre alma y alas omitidos.","Registro de líneas del PDF general, envolvente de 20 × 10 m; eje local 1 al norte y acceso del lado A al oeste. Estimación de trabajo de implantación de ±0,15 m, pendiente de CAD; no constituye una precisión topográfica garantizada."] | {"horizontalStatus":"derivado","verticalStatus":"provisional","baseElevationM":285.95,"note":"Registro de líneas del PDF general, envolvente de 20 × 10 m; eje local 1 al norte y acceso del lado A al oeste. Estimación de trabajo de implantación de ±0,15 m, pendiente de CAD; no constituye una precisión topográfica garantizada."} | {"boundingBoxM":{"min":[17.208668,86.334214,4.56],"max":[26.3737,87.885856,5.15]},"extentsM":[9.165032,1.551642,0.59],"meshSurfaceM2":21.724377,"meshVolumeM3":0.202802,"closedSolid":true,"basis":"Geometría triangulada releída del IFC; envolventes y magnitudes no contractuales."} | {"material":true,"document":true,"quantities":true,"containerGuid":"3ztlotcerHPueDgxP84R6z","containerName":"Planta baja"} | {"id":"structure","name":"Estructura"} | {"profileId":"steel_structural","name":"Acero estructural · protección gris","materialName":"Acero estructural S355JR","physicalMaterialStatus":"known","physicalMaterialSource":"EST-OF-20260710 · Estructura B102 / p. 3, B103 / p. 4","appearanceStatus":"criterio_visual","appearanceBasis":"S355JR consta en la documentación; protección superficial gris adoptada para visualización, sin especificación de pintura confirmada.","note":"La apariencia gráfica no modifica ni confirma la especificación física del material."} | {"elementId":"office_0250","ifcGuid":"2NBky5ghvSOuMW62KWi0D$","ifcClass":"IfcBeam","buildingId":"office","buildingName":"Edificio de oficinas","sourceDocumentId":"EST-OF-20260710","sourceRepresentationKind":"documentary_mesh"} | {"layerId":"structure","layerName":"Estructura","role":"Viga","basis":"Clasificación por función del elemento; no modifica las especificaciones documentales."} | structure | {"profileId":"steel_structural","name":"Acero estructural · protección gris","status":"criterio_visual","basis":"S355JR consta en la documentación; protección superficial gris adoptada para visualización, sin especificación de pintura confirmada.","physicalMaterialUnchanged":true} | EST-OF-20260710 · Estructura B102 / p. 3, B103 / p. 4 | Perfil y dimensiones XY documentados o deducidos; cota de viga deducida de la cabeza de pilar o del intradós de la placa prefabricada. | HEA600 | https://sections.arcelormittal.com/repository2/Sections/5_1_5_ArcelorMittal_FR_EN_RU_web.pdf | 86 | Acuerdos de unión entre alma y alas omitidos. | Ejes unidos a centros de pilares o vigas; chapas de unión y longitudes libres sin desarrollar. | En bombas, la cabeza de viga sigue el plano de pilares con pendiente del 5 %. En oficinas, se adopta cabeza de viga a +4,200 m bajo la placa; el encuentro con pilares a +5,000 m requiere revisión. | Registro de líneas del PDF general, envolvente de 20 × 10 m; eje local 1 al norte y acceso del lado A al oeste. Estimación de trabajo de implantación de ±0,15 m, pendiente de CAD; no constituye una precisión topográfica garantizada. | Estructura | EST-OF-20260710 · Estructura B102 / p. 3, B103 / p. 4 | 285.95 | Estructura | Acero estructural · protección gris | 590 | 300 | 13 | 25 | steel_structural | [0.396078,0.454902,0.482353] | 0.52 | 0.35 | S355JR consta en la documentación; protección superficial gris adoptada para visualización, sin especificación de pintura confirmada. | Estructura; BIM · Estructura | El plano general de 2026-07-31 mantiene el edificio de oficinas de 200 m², mientras documentación anterior indica su supresión. Se conserva lo dibujado, pendiente de confirmación de la propiedad y del equipo de diseño.
Edificio de oficinas · viga de cubierta HEA600 · 7 | Planos de estructura del edificio de oficinas; Planos de estructura del edificio de oficinas | Acero estructural S355JR | 0.3 × 9.21 × 0.59 | 289.56 | 290.15 | 0.202804 | office_0251 | 9.16503 | 1.55164 | 0.59 | 21.7244 | 0.202805 | office | Edificio de oficinas | {"name":"Acero estructural S355JR","source":"EST-OF-20260710 · Estructura B102 / p. 3, B103 / p. 4","status":"known"} | {"documented":[{"label":"Perfil","value":"HEA600","unit":"designación","source":"EST-OF-20260710 · Estructura B102 / p. 3, B103 / p. 4","status":"documentado"},{"label":"Canto nominal del perfil","value":590,"unit":"mm","source":"Catálogo de perfiles ArcelorMittal · 86","status":"documentado"},{"label":"Anchura nominal de ala","value":300,"unit":"mm","source":"Catálogo de perfiles ArcelorMittal · 86","status":"documentado"},{"label":"Espesor nominal de alma","value":13,"unit":"mm","source":"Catálogo de perfiles ArcelorMittal · 86","status":"documentado"},{"label":"Espesor nominal de ala","value":25,"unit":"mm","source":"Catálogo de perfiles ArcelorMittal · 86","status":"documentado"}],"geometry":[{"label":"Dimensiones de la caja local del elemento (X, Y, Z)","value":"0.3 × 9.21 × 0.59","unit":"m","source":"Malla triangulada del elemento en ejes locales del edificio","status":"derivado"},{"label":"Cota mínima absoluta de la malla","value":289.56,"unit":"m","source":"Malla de proyecto y origen altimétrico 285 m","status":"derivado"},{"label":"Cota máxima absoluta de la malla","value":290.15,"unit":"m","source":"Malla de proyecto y origen altimétrico 285 m","status":"derivado"},{"label":"Volumen geométrico bruto","value":0.202804,"unit":"m³","source":"Malla cerrada del elemento","status":"derivado"}],"notes":["Las dimensiones documentadas proceden de anotaciones o cuadros; la caja y el volumen se calculan a partir de la malla.","El volumen es exclusivamente geométrico y bruto; no representa una medición neta de material ni una cantidad de compra."]} | {"documentId":"EST-OF-20260710","title":"Planos de estructura del edificio de oficinas","date":"2026-07-10","sheet":"Estructura B102 / p. 3, B103 / p. 4"} | provisional | ["En bombas, la cabeza de viga sigue el plano de pilares con pendiente del 5 %. En oficinas, se adopta cabeza de viga a +4,200 m bajo la placa; el encuentro con pilares a +5,000 m requiere revisión.","El plano general de 2026-07-31 mantiene el edificio de oficinas de 200 m², mientras documentación anterior indica su supresión. Se conserva lo dibujado, pendiente de confirmación de la propiedad y del equipo de diseño.","Ejes unidos a centros de pilares o vigas; chapas de unión y longitudes libres sin desarrollar.","Acuerdos de unión entre alma y alas omitidos.","Registro de líneas del PDF general, envolvente de 20 × 10 m; eje local 1 al norte y acceso del lado A al oeste. Estimación de trabajo de implantación de ±0,15 m, pendiente de CAD; no constituye una precisión topográfica garantizada."] | {"horizontalStatus":"derivado","verticalStatus":"provisional","baseElevationM":285.95,"note":"Registro de líneas del PDF general, envolvente de 20 × 10 m; eje local 1 al norte y acceso del lado A al oeste. Estimación de trabajo de implantación de ±0,15 m, pendiente de CAD; no constituye una precisión topográfica garantizada."} | {"boundingBoxM":{"min":[16.551484,81.554179,4.56],"max":[25.716516,83.105821,5.15]},"extentsM":[9.165032,1.551642,0.59],"meshSurfaceM2":21.724368,"meshVolumeM3":0.202805,"closedSolid":true,"basis":"Geometría triangulada releída del IFC; envolventes y magnitudes no contractuales."} | {"material":true,"document":true,"quantities":true,"containerGuid":"3ztlotcerHPueDgxP84R6z","containerName":"Planta baja"} | {"id":"structure","name":"Estructura"} | {"profileId":"steel_structural","name":"Acero estructural · protección gris","materialName":"Acero estructural S355JR","physicalMaterialStatus":"known","physicalMaterialSource":"EST-OF-20260710 · Estructura B102 / p. 3, B103 / p. 4","appearanceStatus":"criterio_visual","appearanceBasis":"S355JR consta en la documentación; protección superficial gris adoptada para visualización, sin especificación de pintura confirmada.","note":"La apariencia gráfica no modifica ni confirma la especificación física del material."} | {"elementId":"office_0251","ifcGuid":"02sTgWDrvPffjwB_2NXA1f","ifcClass":"IfcBeam","buildingId":"office","buildingName":"Edificio de oficinas","sourceDocumentId":"EST-OF-20260710","sourceRepresentationKind":"documentary_mesh"} | {"layerId":"structure","layerName":"Estructura","role":"Viga","basis":"Clasificación por función del elemento; no modifica las especificaciones documentales."} | structure | {"profileId":"steel_structural","name":"Acero estructural · protección gris","status":"criterio_visual","basis":"S355JR consta en la documentación; protección superficial gris adoptada para visualización, sin especificación de pintura confirmada.","physicalMaterialUnchanged":true} | EST-OF-20260710 · Estructura B102 / p. 3, B103 / p. 4 | Perfil y dimensiones XY documentados o deducidos; cota de viga deducida de la cabeza de pilar o del intradós de la placa prefabricada. | HEA600 | https://sections.arcelormittal.com/repository2/Sections/5_1_5_ArcelorMittal_FR_EN_RU_web.pdf | 86 | Acuerdos de unión entre alma y alas omitidos. | Ejes unidos a centros de pilares o vigas; chapas de unión y longitudes libres sin desarrollar. | En bombas, la cabeza de viga sigue el plano de pilares con pendiente del 5 %. En oficinas, se adopta cabeza de viga a +4,200 m bajo la placa; el encuentro con pilares a +5,000 m requiere revisión. | Registro de líneas del PDF general, envolvente de 20 × 10 m; eje local 1 al norte y acceso del lado A al oeste. Estimación de trabajo de implantación de ±0,15 m, pendiente de CAD; no constituye una precisión topográfica garantizada. | Estructura | EST-OF-20260710 · Estructura B102 / p. 3, B103 / p. 4 | 285.95 | Estructura | Acero estructural · protección gris | 590 | 300 | 13 | 25 | steel_structural | [0.396078,0.454902,0.482353] | 0.52 | 0.35 | S355JR consta en la documentación; protección superficial gris adoptada para visualización, sin especificación de pintura confirmada. | Estructura; BIM · Estructura | El plano general de 2026-07-31 mantiene el edificio de oficinas de 200 m², mientras documentación anterior indica su supresión. Se conserva lo dibujado, pendiente de confirmación de la propiedad y del equipo de diseño.
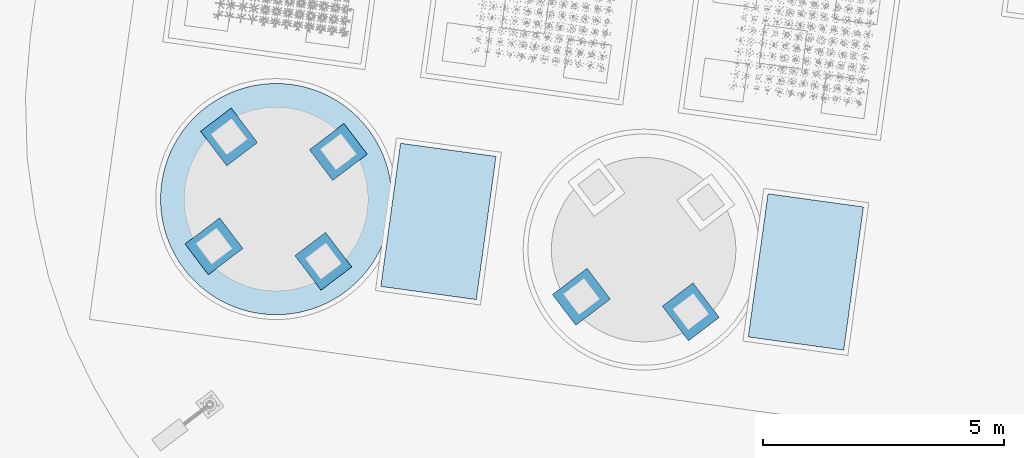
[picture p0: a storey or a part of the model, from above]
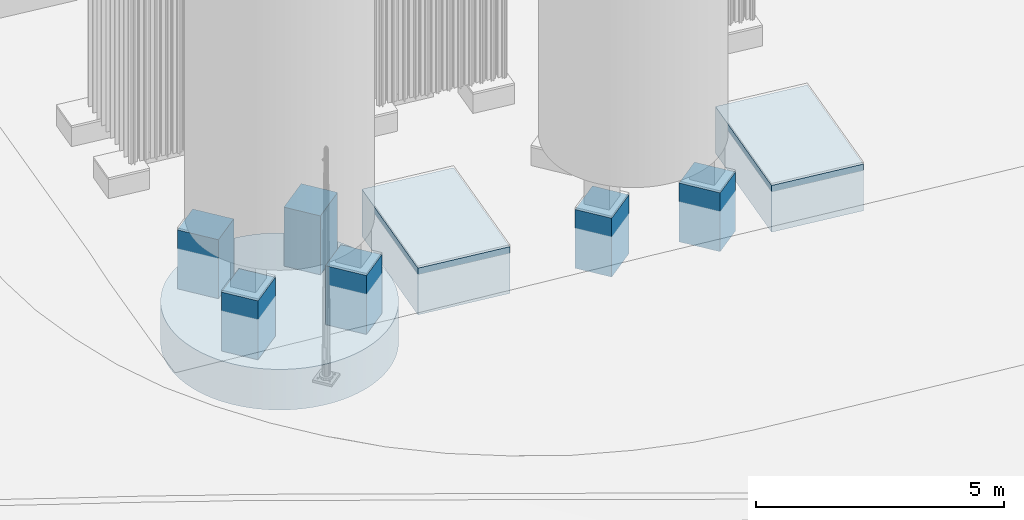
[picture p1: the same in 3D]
Properties of the parts of a building model (IFC4), part 3 of 134

# IfcBeam (24)
Name | Document | Material = JH_Trazabilidad, Material = name | Dimensiones de la caja local del elemento (X, Y, Z) | Cota mínima absoluta de la malla (m) | Cota máxima absoluta de la malla (m) | Volumen geométrico bruto (m3) = Volumen geométrico (m³) | Reference = Identificador del elemento = Identificador | ExtensionX (m) | ExtensionY (m) | ExtensionZ (m) | SuperficieDeLaMalla (m2) | VolumenGeometrico (m3) = GrossVolume (m3) | buildingId | buildingName = Edificio | material | dimensions | JH_InformacionBIM, source = DocumentoFuente | status = EstadoDeInformacion | issues = IncidenciasPendientes | positioning = PosicionYEstado | geometryMetrics | ifcAssociations | visualLayer | materialAppearance | visualizationIdentity | classification | layerId = IdentificadorCapa | appearance | Planos de referencia | Base geométrica | Perfil laminado = JH_DimensionesDocumentadas, Perfil | Catálogo del perfil | Página PDF del catálogo | Acuerdos del perfil | Extremos y uniones | Coordinación de cotas pendiente | Estado de la implantación | Disciplina | Referencia del material = JH_EvidenciaDeMaterial, source | Cota de planta baja terminada (m) | Capa BIM = NombreCapa | Acabado de visualización = Acabado | Canto nominal del perfil | Anchura nominal de ala | Espesor nominal de alma | Espesor nominal de ala | JH_AcabadoVisual, Perfil | ColorRGB | Rugosidad | Metallicidad | Referencia | Group | Discrepancia entre versiones
Edificio de oficinas · viga de cubierta HEA600 · 8 | Planos de estructura del edificio de oficinas; Planos de estructura del edificio de oficinas | Acero estructural S355JR | 0.3 × 9.21 × 0.59 | 289.56 | 290.15 | 0.202804 | office_0252 | 9.16503 | 1.55164 | 0.59 | 21.7244 | 0.202802 | office | Edificio de oficinas | {"name":"Acero estructural S355JR","source":"EST-OF-20260710 · Estructura B102 / p. 3, B103 / p. 4","status":"known"} | {"documented":[{"label":"Perfil","value":"HEA600","unit":"designación","source":"EST-OF-20260710 · Estructura B102 / p. 3, B103 / p. 4","status":"documentado"},{"label":"Canto nominal del perfil","value":590,"unit":"mm","source":"Catálogo de perfiles ArcelorMittal · 86","status":"documentado"},{"label":"Anchura nominal de ala","value":300,"unit":"mm","source":"Catálogo de perfiles ArcelorMittal · 86","status":"documentado"},{"label":"Espesor nominal de alma","value":13,"unit":"mm","source":"Catálogo de perfiles ArcelorMittal · 86","status":"documentado"},{"label":"Espesor nominal de ala","value":25,"unit":"mm","source":"Catálogo de perfiles ArcelorMittal · 86","status":"documentado"}],"geometry":[{"label":"Dimensiones de la caja local del elemento (X, Y, Z)","value":"0.3 × 9.21 × 0.59","unit":"m","source":"Malla triangulada del elemento en ejes locales del edificio","status":"derivado"},{"label":"Cota mínima absoluta de la malla","value":289.56,"unit":"m","source":"Malla de proyecto y origen altimétrico 285 m","status":"derivado"},{"label":"Cota máxima absoluta de la malla","value":290.15,"unit":"m","source":"Malla de proyecto y origen altimétrico 285 m","status":"derivado"},{"label":"Volumen geométrico bruto","value":0.202804,"unit":"m³","source":"Malla cerrada del elemento","status":"derivado"}],"notes":["Las dimensiones documentadas proceden de anotaciones o cuadros; la caja y el volumen se calculan a partir de la malla.","El volumen es exclusivamente geométrico y bruto; no representa una medición neta de material ni una cantidad de compra."]} | {"documentId":"EST-OF-20260710","title":"Planos de estructura del edificio de oficinas","date":"2026-07-10","sheet":"Estructura B102 / p. 3, B103 / p. 4"} | provisional | ["En bombas, la cabeza de viga sigue el plano de pilares con pendiente del 5 %. En oficinas, se adopta cabeza de viga a +4,200 m bajo la placa; el encuentro con pilares a +5,000 m requiere revisión.","El plano general de 2026-07-31 mantiene el edificio de oficinas de 200 m², mientras documentación anterior indica su supresión. Se conserva lo dibujado, pendiente de confirmación de la propiedad y del equipo de diseño.","Ejes unidos a centros de pilares o vigas; chapas de unión y longitudes libres sin desarrollar.","Acuerdos de unión entre alma y alas omitidos.","Registro de líneas del PDF general, envolvente de 20 × 10 m; eje local 1 al norte y acceso del lado A al oeste. Estimación de trabajo de implantación de ±0,15 m, pendiente de CAD; no constituye una precisión topográfica garantizada."] | {"horizontalStatus":"derivado","verticalStatus":"provisional","baseElevationM":285.95,"note":"Registro de líneas del PDF general, envolvente de 20 × 10 m; eje local 1 al norte y acceso del lado A al oeste. Estimación de trabajo de implantación de ±0,15 m, pendiente de CAD; no constituye una precisión topográfica garantizada."} | {"boundingBoxM":{"min":[15.8943,76.774144,4.56],"max":[25.059332,78.325786,5.15]},"extentsM":[9.165032,1.551642,0.59],"meshSurfaceM2":21.724377,"meshVolumeM3":0.202802,"closedSolid":true,"basis":"Geometría triangulada releída del IFC; envolventes y magnitudes no contractuales."} | {"material":true,"document":true,"quantities":true,"containerGuid":"3ztlotcerHPueDgxP84R6z","containerName":"Planta baja"} | {"id":"structure","name":"Estructura"} | {"profileId":"steel_structural","name":"Acero estructural · protección gris","materialName":"Acero estructural S355JR","physicalMaterialStatus":"known","physicalMaterialSource":"EST-OF-20260710 · Estructura B102 / p. 3, B103 / p. 4","appearanceStatus":"criterio_visual","appearanceBasis":"S355JR consta en la documentación; protección superficial gris adoptada para visualización, sin especificación de pintura confirmada.","note":"La apariencia gráfica no modifica ni confirma la especificación física del material."} | {"elementId":"office_0252","ifcGuid":"1OcZs$T6nS3AmU_H1IwxAn","ifcClass":"IfcBeam","buildingId":"office","buildingName":"Edificio de oficinas","sourceDocumentId":"EST-OF-20260710","sourceRepresentationKind":"documentary_mesh"} | {"layerId":"structure","layerName":"Estructura","role":"Viga","basis":"Clasificación por función del elemento; no modifica las especificaciones documentales."} | structure | {"profileId":"steel_structural","name":"Acero estructural · protección gris","status":"criterio_visual","basis":"S355JR consta en la documentación; protección superficial gris adoptada para visualización, sin especificación de pintura confirmada.","physicalMaterialUnchanged":true} | EST-OF-20260710 · Estructura B102 / p. 3, B103 / p. 4 | Perfil y dimensiones XY documentados o deducidos; cota de viga deducida de la cabeza de pilar o del intradós de la placa prefabricada. | HEA600 | https://sections.arcelormittal.com/repository2/Sections/5_1_5_ArcelorMittal_FR_EN_RU_web.pdf | 86 | Acuerdos de unión entre alma y alas omitidos. | Ejes unidos a centros de pilares o vigas; chapas de unión y longitudes libres sin desarrollar. | En bombas, la cabeza de viga sigue el plano de pilares con pendiente del 5 %. En oficinas, se adopta cabeza de viga a +4,200 m bajo la placa; el encuentro con pilares a +5,000 m requiere revisión. | Registro de líneas del PDF general, envolvente de 20 × 10 m; eje local 1 al norte y acceso del lado A al oeste. Estimación de trabajo de implantación de ±0,15 m, pendiente de CAD; no constituye una precisión topográfica garantizada. | Estructura | EST-OF-20260710 · Estructura B102 / p. 3, B103 / p. 4 | 285.95 | Estructura | Acero estructural · protección gris | 590 | 300 | 13 | 25 | steel_structural | [0.396078,0.454902,0.482353] | 0.52 | 0.35 | S355JR consta en la documentación; protección superficial gris adoptada para visualización, sin especificación de pintura confirmada. | Estructura; BIM · Estructura | El plano general de 2026-07-31 mantiene el edificio de oficinas de 200 m², mientras documentación anterior indica su supresión. Se conserva lo dibujado, pendiente de confirmación de la propiedad y del equipo de diseño.
Edificio de oficinas · viga de cubierta HEA600 · 9 | Planos de estructura del edificio de oficinas; Planos de estructura del edificio de oficinas | Acero estructural S355JR | 0.3 × 9.21 × 0.59 | 289.56 | 290.15 | 0.202804 | office_0253 | 9.16503 | 1.55164 | 0.59 | 21.7244 | 0.202802 | office | Edificio de oficinas | {"name":"Acero estructural S355JR","source":"EST-OF-20260710 · Estructura B102 / p. 3, B103 / p. 4","status":"known"} | {"documented":[{"label":"Perfil","value":"HEA600","unit":"designación","source":"EST-OF-20260710 · Estructura B102 / p. 3, B103 / p. 4","status":"documentado"},{"label":"Canto nominal del perfil","value":590,"unit":"mm","source":"Catálogo de perfiles ArcelorMittal · 86","status":"documentado"},{"label":"Anchura nominal de ala","value":300,"unit":"mm","source":"Catálogo de perfiles ArcelorMittal · 86","status":"documentado"},{"label":"Espesor nominal de alma","value":13,"unit":"mm","source":"Catálogo de perfiles ArcelorMittal · 86","status":"documentado"},{"label":"Espesor nominal de ala","value":25,"unit":"mm","source":"Catálogo de perfiles ArcelorMittal · 86","status":"documentado"}],"geometry":[{"label":"Dimensiones de la caja local del elemento (X, Y, Z)","value":"0.3 × 9.21 × 0.59","unit":"m","source":"Malla triangulada del elemento en ejes locales del edificio","status":"derivado"},{"label":"Cota mínima absoluta de la malla","value":289.56,"unit":"m","source":"Malla de proyecto y origen altimétrico 285 m","status":"derivado"},{"label":"Cota máxima absoluta de la malla","value":290.15,"unit":"m","source":"Malla de proyecto y origen altimétrico 285 m","status":"derivado"},{"label":"Volumen geométrico bruto","value":0.202804,"unit":"m³","source":"Malla cerrada del elemento","status":"derivado"}],"notes":["Las dimensiones documentadas proceden de anotaciones o cuadros; la caja y el volumen se calculan a partir de la malla.","El volumen es exclusivamente geométrico y bruto; no representa una medición neta de material ni una cantidad de compra."]} | {"documentId":"EST-OF-20260710","title":"Planos de estructura del edificio de oficinas","date":"2026-07-10","sheet":"Estructura B102 / p. 3, B103 / p. 4"} | provisional | ["En bombas, la cabeza de viga sigue el plano de pilares con pendiente del 5 %. En oficinas, se adopta cabeza de viga a +4,200 m bajo la placa; el encuentro con pilares a +5,000 m requiere revisión.","El plano general de 2026-07-31 mantiene el edificio de oficinas de 200 m², mientras documentación anterior indica su supresión. Se conserva lo dibujado, pendiente de confirmación de la propiedad y del equipo de diseño.","Ejes unidos a centros de pilares o vigas; chapas de unión y longitudes libres sin desarrollar.","Acuerdos de unión entre alma y alas omitidos.","Registro de líneas del PDF general, envolvente de 20 × 10 m; eje local 1 al norte y acceso del lado A al oeste. Estimación de trabajo de implantación de ±0,15 m, pendiente de CAD; no constituye una precisión topográfica garantizada."] | {"horizontalStatus":"derivado","verticalStatus":"provisional","baseElevationM":285.95,"note":"Registro de líneas del PDF general, envolvente de 20 × 10 m; eje local 1 al norte y acceso del lado A al oeste. Estimación de trabajo de implantación de ±0,15 m, pendiente de CAD; no constituye una precisión topográfica garantizada."} | {"boundingBoxM":{"min":[15.237116,71.994109,4.56],"max":[24.402148,73.545751,5.15]},"extentsM":[9.165032,1.551642,0.59],"meshSurfaceM2":21.724379,"meshVolumeM3":0.202802,"closedSolid":true,"basis":"Geometría triangulada releída del IFC; envolventes y magnitudes no contractuales."} | {"material":true,"document":true,"quantities":true,"containerGuid":"3ztlotcerHPueDgxP84R6z","containerName":"Planta baja"} | {"id":"structure","name":"Estructura"} | {"profileId":"steel_structural","name":"Acero estructural · protección gris","materialName":"Acero estructural S355JR","physicalMaterialStatus":"known","physicalMaterialSource":"EST-OF-20260710 · Estructura B102 / p. 3, B103 / p. 4","appearanceStatus":"criterio_visual","appearanceBasis":"S355JR consta en la documentación; protección superficial gris adoptada para visualización, sin especificación de pintura confirmada.","note":"La apariencia gráfica no modifica ni confirma la especificación física del material."} | {"elementId":"office_0253","ifcGuid":"1_mndWo7jJIu_l$0aTxR6Y","ifcClass":"IfcBeam","buildingId":"office","buildingName":"Edificio de oficinas","sourceDocumentId":"EST-OF-20260710","sourceRepresentationKind":"documentary_mesh"} | {"layerId":"structure","layerName":"Estructura","role":"Viga","basis":"Clasificación por función del elemento; no modifica las especificaciones documentales."} | structure | {"profileId":"steel_structural","name":"Acero estructural · protección gris","status":"criterio_visual","basis":"S355JR consta en la documentación; protección superficial gris adoptada para visualización, sin especificación de pintura confirmada.","physicalMaterialUnchanged":true} | EST-OF-20260710 · Estructura B102 / p. 3, B103 / p. 4 | Perfil y dimensiones XY documentados o deducidos; cota de viga deducida de la cabeza de pilar o del intradós de la placa prefabricada. | HEA600 | https://sections.arcelormittal.com/repository2/Sections/5_1_5_ArcelorMittal_FR_EN_RU_web.pdf | 86 | Acuerdos de unión entre alma y alas omitidos. | Ejes unidos a centros de pilares o vigas; chapas de unión y longitudes libres sin desarrollar. | En bombas, la cabeza de viga sigue el plano de pilares con pendiente del 5 %. En oficinas, se adopta cabeza de viga a +4,200 m bajo la placa; el encuentro con pilares a +5,000 m requiere revisión. | Registro de líneas del PDF general, envolvente de 20 × 10 m; eje local 1 al norte y acceso del lado A al oeste. Estimación de trabajo de implantación de ±0,15 m, pendiente de CAD; no constituye una precisión topográfica garantizada. | Estructura | EST-OF-20260710 · Estructura B102 / p. 3, B103 / p. 4 | 285.95 | Estructura | Acero estructural · protección gris | 590 | 300 | 13 | 25 | steel_structural | [0.396078,0.454902,0.482353] | 0.52 | 0.35 | S355JR consta en la documentación; protección superficial gris adoptada para visualización, sin especificación de pintura confirmada. | Estructura; BIM · Estructura | El plano general de 2026-07-31 mantiene el edificio de oficinas de 200 m², mientras documentación anterior indica su supresión. Se conserva lo dibujado, pendiente de confirmación de la propiedad y del equipo de diseño.
Edificio de oficinas · viga de atado VC1 · 1 | Planos de estructura del edificio de oficinas; Planos de estructura del edificio de oficinas | Hormigón armado HA-30 | 9.65 × 0.3 × 0.6 | 284.35 | 284.95 | 1.737 | office_0260 | 1.61157 | 9.60093 | 0.6 | 17.73 | 1.737 | office | Edificio de oficinas | {"name":"Hormigón armado HA-30","source":"EST-OF-20260710 · Estructura B201 / p. 5; nota de resistencia de zapatas y vigas de atado","status":"known"} | {"documented":[{"label":"Cota superior absoluta","value":284.95,"unit":"m","source":"EST-OF-20260710 · Estructura B201 / p. 5","status":"documentado"},{"label":"Anchura","value":0.3,"unit":"m","source":"EST-OF-20260710 · Estructura B201 / p. 5","status":"documentado"},{"label":"Altura de sección","value":0.6,"unit":"m","source":"EST-OF-20260710 · Estructura B201 / p. 5","status":"documentado"}],"geometry":[{"label":"Dimensiones de la caja local del elemento (X, Y, Z)","value":"9.65 × 0.3 × 0.6","unit":"m","source":"Malla triangulada del elemento en ejes locales del edificio","status":"derivado"},{"label":"Cota mínima absoluta de la malla","value":284.35,"unit":"m","source":"Malla de proyecto y origen altimétrico 285 m","status":"derivado"},{"label":"Cota máxima absoluta de la malla","value":284.95,"unit":"m","source":"Malla de proyecto y origen altimétrico 285 m","status":"derivado"},{"label":"Volumen geométrico bruto","value":1.737,"unit":"m³","source":"Malla cerrada del elemento","status":"derivado"}],"notes":["Las dimensiones documentadas proceden de anotaciones o cuadros; la caja y el volumen se calculan a partir de la malla.","El volumen es exclusivamente geométrico y bruto; no representa una medición neta de material ni una cantidad de compra."]} | {"documentId":"EST-OF-20260710","title":"Planos de estructura del edificio de oficinas","date":"2026-07-10","sheet":"Estructura B201 / p. 5"} | derivado | ["El plano general de 2026-07-31 mantiene el edificio de oficinas de 200 m², mientras documentación anterior indica su supresión. Se conserva lo dibujado, pendiente de confirmación de la propiedad y del equipo de diseño.","Excentricidad de las vigas de atado respecto a los muros simplificada mediante ejes; armaduras no modeladas.","Registro de líneas del PDF general, envolvente de 20 × 10 m; eje local 1 al norte y acceso del lado A al oeste. Estimación de trabajo de implantación de ±0,15 m, pendiente de CAD; no constituye una precisión topográfica garantizada."] | {"horizontalStatus":"derivado","verticalStatus":"derivado","baseElevationM":285.95,"note":"Registro de líneas del PDF general, envolvente de 20 × 10 m; eje local 1 al norte y acceso del lado A al oeste. Estimación de trabajo de implantación de ±0,15 m, pendiente de CAD; no constituye una precisión topográfica garantizada."} | {"boundingBoxM":{"min":[16.423313,82.936788,-0.65],"max":[18.034885,92.53772,-0.05]},"extentsM":[1.611572,9.600932,0.6],"meshSurfaceM2":17.729997,"meshVolumeM3":1.736999,"closedSolid":true,"basis":"Geometría triangulada releída del IFC; envolventes y magnitudes no contractuales."} | {"material":true,"document":true,"quantities":true,"containerGuid":"3ztlotcerHPueDgxP84R6z","containerName":"Planta baja"} | {"id":"foundations","name":"Cimentaciones"} | {"profileId":"concrete_ha30","name":"Hormigón HA-30","materialName":"Hormigón armado HA-30","physicalMaterialStatus":"known","physicalMaterialSource":"EST-OF-20260710 · Estructura B201 / p. 5; nota de resistencia de zapatas y vigas de atado","appearanceStatus":"criterio_visual","appearanceBasis":"Interpretación visual del material documental; el acabado, tono y parámetros PBR no son una especificación contractual.","note":"La apariencia gráfica no modifica ni confirma la especificación física del material."} | {"elementId":"office_0260","ifcGuid":"1NKvTbsGDR8w1_QV$y3VXQ","ifcClass":"IfcBeam","buildingId":"office","buildingName":"Edificio de oficinas","sourceDocumentId":"EST-OF-20260710","sourceRepresentationKind":"documentary_mesh"} | {"layerId":"foundations","layerName":"Cimentaciones","role":"Viga","basis":"Clasificación por función del elemento; no modifica las especificaciones documentales."} | foundations | {"profileId":"concrete_ha30","name":"Hormigón HA-30","status":"criterio_visual","basis":"Interpretación visual del material documental; el acabado, tono y parámetros PBR no son una especificación contractual.","physicalMaterialUnchanged":true} | EST-OF-20260710 · Estructura B201 / p. 5 | Sección y cota superior documentadas en el cuadro y las notas generales; trazado simplificado uniendo los centros de las zapatas. |  |  |  |  |  |  | Registro de líneas del PDF general, envolvente de 20 × 10 m; eje local 1 al norte y acceso del lado A al oeste. Estimación de trabajo de implantación de ±0,15 m, pendiente de CAD; no constituye una precisión topográfica garantizada. | Cimentación | EST-OF-20260710 · Estructura B201 / p. 5; nota de resistencia de zapatas y vigas de atado | 285.95 | Cimentaciones | Hormigón HA-30 |  |  |  |  | concrete_ha30 | [0.658824,0.658824,0.623529] | 0.94 | 0 | Interpretación visual del material documental; el acabado, tono y parámetros PBR no son una especificación contractual. | Cimentación; BIM · Cimentaciones | El plano general de 2026-07-31 mantiene el edificio de oficinas de 200 m², mientras documentación anterior indica su supresión. Se conserva lo dibujado, pendiente de confirmación de la propiedad y del equipo de diseño. | JH_Trazabilidad - Anchura (m): 0.3; Altura de sección (m): 0.6; Cota superior absoluta (m): 284.95; Simplificación geométrica: Excentricidad de las vigas de atado respecto a los muros simplificada mediante ejes; armaduras no modeladas.; Discrepancia pendiente: No se ha identificado una discrepancia de sección en la documentación revisada.; JH_DimensionesDocumentadas - Cota superior absoluta: 284.95 m; Anchura: 0.3 m; Altura de sección: 0.6 m
Edificio de oficinas · viga de atado VC1 · 2 | Planos de estructura del edificio de oficinas; Planos de estructura del edificio de oficinas | Hormigón armado HA-30 | 9.65 × 0.3 × 0.6 | 284.35 | 284.95 | 1.737 | office_0261 | 1.61157 | 9.60093 | 0.6 | 17.73 | 1.737 | office | Edificio de oficinas | {"name":"Hormigón armado HA-30","source":"EST-OF-20260710 · Estructura B201 / p. 5; nota de resistencia de zapatas y vigas de atado","status":"known"} | {"documented":[{"label":"Cota superior absoluta","value":284.95,"unit":"m","source":"EST-OF-20260710 · Estructura B201 / p. 5","status":"documentado"},{"label":"Anchura","value":0.3,"unit":"m","source":"EST-OF-20260710 · Estructura B201 / p. 5","status":"documentado"},{"label":"Altura de sección","value":0.6,"unit":"m","source":"EST-OF-20260710 · Estructura B201 / p. 5","status":"documentado"}],"geometry":[{"label":"Dimensiones de la caja local del elemento (X, Y, Z)","value":"9.65 × 0.3 × 0.6","unit":"m","source":"Malla triangulada del elemento en ejes locales del edificio","status":"derivado"},{"label":"Cota mínima absoluta de la malla","value":284.35,"unit":"m","source":"Malla de proyecto y origen altimétrico 285 m","status":"derivado"},{"label":"Cota máxima absoluta de la malla","value":284.95,"unit":"m","source":"Malla de proyecto y origen altimétrico 285 m","status":"derivado"},{"label":"Volumen geométrico bruto","value":1.737,"unit":"m³","source":"Malla cerrada del elemento","status":"derivado"}],"notes":["Las dimensiones documentadas proceden de anotaciones o cuadros; la caja y el volumen se calculan a partir de la malla.","El volumen es exclusivamente geométrico y bruto; no representa una medición neta de material ni una cantidad de compra."]} | {"documentId":"EST-OF-20260710","title":"Planos de estructura del edificio de oficinas","date":"2026-07-10","sheet":"Estructura B201 / p. 5"} | derivado | ["El plano general de 2026-07-31 mantiene el edificio de oficinas de 200 m², mientras documentación anterior indica su supresión. Se conserva lo dibujado, pendiente de confirmación de la propiedad y del equipo de diseño.","Excentricidad de las vigas de atado respecto a los muros simplificada mediante ejes; armaduras no modeladas.","Registro de líneas del PDF general, envolvente de 20 × 10 m; eje local 1 al norte y acceso del lado A al oeste. Estimación de trabajo de implantación de ±0,15 m, pendiente de CAD; no constituye una precisión topográfica garantizada."] | {"horizontalStatus":"derivado","verticalStatus":"derivado","baseElevationM":285.95,"note":"Registro de líneas del PDF general, envolvente de 20 × 10 m; eje local 1 al norte y acceso del lado A al oeste. Estimación de trabajo de implantación de ±0,15 m, pendiente de CAD; no constituye una precisión topográfica garantizada."} | {"boundingBoxM":{"min":[15.108945,73.376719,-0.65],"max":[16.720517,82.97765,-0.05]},"extentsM":[1.611572,9.600931,0.6],"meshSurfaceM2":17.729995,"meshVolumeM3":1.736999,"closedSolid":true,"basis":"Geometría triangulada releída del IFC; envolventes y magnitudes no contractuales."} | {"material":true,"document":true,"quantities":true,"containerGuid":"3ztlotcerHPueDgxP84R6z","containerName":"Planta baja"} | {"id":"foundations","name":"Cimentaciones"} | {"profileId":"concrete_ha30","name":"Hormigón HA-30","materialName":"Hormigón armado HA-30","physicalMaterialStatus":"known","physicalMaterialSource":"EST-OF-20260710 · Estructura B201 / p. 5; nota de resistencia de zapatas y vigas de atado","appearanceStatus":"criterio_visual","appearanceBasis":"Interpretación visual del material documental; el acabado, tono y parámetros PBR no son una especificación contractual.","note":"La apariencia gráfica no modifica ni confirma la especificación física del material."} | {"elementId":"office_0261","ifcGuid":"1SKOcLLI1QEwMw5vyha81K","ifcClass":"IfcBeam","buildingId":"office","buildingName":"Edificio de oficinas","sourceDocumentId":"EST-OF-20260710","sourceRepresentationKind":"documentary_mesh"} | {"layerId":"foundations","layerName":"Cimentaciones","role":"Viga","basis":"Clasificación por función del elemento; no modifica las especificaciones documentales."} | foundations | {"profileId":"concrete_ha30","name":"Hormigón HA-30","status":"criterio_visual","basis":"Interpretación visual del material documental; el acabado, tono y parámetros PBR no son una especificación contractual.","physicalMaterialUnchanged":true} | EST-OF-20260710 · Estructura B201 / p. 5 | Sección y cota superior documentadas en el cuadro y las notas generales; trazado simplificado uniendo los centros de las zapatas. |  |  |  |  |  |  | Registro de líneas del PDF general, envolvente de 20 × 10 m; eje local 1 al norte y acceso del lado A al oeste. Estimación de trabajo de implantación de ±0,15 m, pendiente de CAD; no constituye una precisión topográfica garantizada. | Cimentación | EST-OF-20260710 · Estructura B201 / p. 5; nota de resistencia de zapatas y vigas de atado | 285.95 | Cimentaciones | Hormigón HA-30 |  |  |  |  | concrete_ha30 | [0.658824,0.658824,0.623529] | 0.94 | 0 | Interpretación visual del material documental; el acabado, tono y parámetros PBR no son una especificación contractual. | Cimentación; BIM · Cimentaciones | El plano general de 2026-07-31 mantiene el edificio de oficinas de 200 m², mientras documentación anterior indica su supresión. Se conserva lo dibujado, pendiente de confirmación de la propiedad y del equipo de diseño. | JH_Trazabilidad - Anchura (m): 0.3; Altura de sección (m): 0.6; Cota superior absoluta (m): 284.95; Simplificación geométrica: Excentricidad de las vigas de atado respecto a los muros simplificada mediante ejes; armaduras no modeladas.; Discrepancia pendiente: No se ha identificado una discrepancia de sección en la documentación revisada.; JH_DimensionesDocumentadas - Cota superior absoluta: 284.95 m; Anchura: 0.3 m; Altura de sección: 0.6 m
Edificio de oficinas · viga de atado VC1 · 3 | Planos de estructura del edificio de oficinas; Planos de estructura del edificio de oficinas | Hormigón armado HA-30 | 9.65 × 0.3 × 0.6 | 284.35 | 284.95 | 1.737 | office_0262 | 1.61157 | 9.60093 | 0.6 | 17.73 | 1.737 | office | Edificio de oficinas | {"name":"Hormigón armado HA-30","source":"EST-OF-20260710 · Estructura B201 / p. 5; nota de resistencia de zapatas y vigas de atado","status":"known"} | {"documented":[{"label":"Cota superior absoluta","value":284.95,"unit":"m","source":"EST-OF-20260710 · Estructura B201 / p. 5","status":"documentado"},{"label":"Anchura","value":0.3,"unit":"m","source":"EST-OF-20260710 · Estructura B201 / p. 5","status":"documentado"},{"label":"Altura de sección","value":0.6,"unit":"m","source":"EST-OF-20260710 · Estructura B201 / p. 5","status":"documentado"}],"geometry":[{"label":"Dimensiones de la caja local del elemento (X, Y, Z)","value":"9.65 × 0.3 × 0.6","unit":"m","source":"Malla triangulada del elemento en ejes locales del edificio","status":"derivado"},{"label":"Cota mínima absoluta de la malla","value":284.35,"unit":"m","source":"Malla de proyecto y origen altimétrico 285 m","status":"derivado"},{"label":"Cota máxima absoluta de la malla","value":284.95,"unit":"m","source":"Malla de proyecto y origen altimétrico 285 m","status":"derivado"},{"label":"Volumen geométrico bruto","value":1.737,"unit":"m³","source":"Malla cerrada del elemento","status":"derivado"}],"notes":["Las dimensiones documentadas proceden de anotaciones o cuadros; la caja y el volumen se calculan a partir de la malla.","El volumen es exclusivamente geométrico y bruto; no representa una medición neta de material ni una cantidad de compra."]} | {"documentId":"EST-OF-20260710","title":"Planos de estructura del edificio de oficinas","date":"2026-07-10","sheet":"Estructura B201 / p. 5"} | derivado | ["El plano general de 2026-07-31 mantiene el edificio de oficinas de 200 m², mientras documentación anterior indica su supresión. Se conserva lo dibujado, pendiente de confirmación de la propiedad y del equipo de diseño.","Excentricidad de las vigas de atado respecto a los muros simplificada mediante ejes; armaduras no modeladas.","Registro de líneas del PDF general, envolvente de 20 × 10 m; eje local 1 al norte y acceso del lado A al oeste. Estimación de trabajo de implantación de ±0,15 m, pendiente de CAD; no constituye una precisión topográfica garantizada."] | {"horizontalStatus":"derivado","verticalStatus":"derivado","baseElevationM":285.95,"note":"Registro de líneas del PDF general, envolvente de 20 × 10 m; eje local 1 al norte y acceso del lado A al oeste. Estimación de trabajo de implantación de ±0,15 m, pendiente de CAD; no constituye una precisión topográfica garantizada."} | {"boundingBoxM":{"min":[25.547483,81.68235,-0.65],"max":[27.159055,91.283281,-0.05]},"extentsM":[1.611572,9.600931,0.6],"meshSurfaceM2":17.729995,"meshVolumeM3":1.736999,"closedSolid":true,"basis":"Geometría triangulada releída del IFC; envolventes y magnitudes no contractuales."} | {"material":true,"document":true,"quantities":true,"containerGuid":"3ztlotcerHPueDgxP84R6z","containerName":"Planta baja"} | {"id":"foundations","name":"Cimentaciones"} | {"profileId":"concrete_ha30","name":"Hormigón HA-30","materialName":"Hormigón armado HA-30","physicalMaterialStatus":"known","physicalMaterialSource":"EST-OF-20260710 · Estructura B201 / p. 5; nota de resistencia de zapatas y vigas de atado","appearanceStatus":"criterio_visual","appearanceBasis":"Interpretación visual del material documental; el acabado, tono y parámetros PBR no son una especificación contractual.","note":"La apariencia gráfica no modifica ni confirma la especificación física del material."} | {"elementId":"office_0262","ifcGuid":"35Rm$fjGrRXelmAIMc$Aw1","ifcClass":"IfcBeam","buildingId":"office","buildingName":"Edificio de oficinas","sourceDocumentId":"EST-OF-20260710","sourceRepresentationKind":"documentary_mesh"} | {"layerId":"foundations","layerName":"Cimentaciones","role":"Viga","basis":"Clasificación por función del elemento; no modifica las especificaciones documentales."} | foundations | {"profileId":"concrete_ha30","name":"Hormigón HA-30","status":"criterio_visual","basis":"Interpretación visual del material documental; el acabado, tono y parámetros PBR no son una especificación contractual.","physicalMaterialUnchanged":true} | EST-OF-20260710 · Estructura B201 / p. 5 | Sección y cota superior documentadas en el cuadro y las notas generales; trazado simplificado uniendo los centros de las zapatas. |  |  |  |  |  |  | Registro de líneas del PDF general, envolvente de 20 × 10 m; eje local 1 al norte y acceso del lado A al oeste. Estimación de trabajo de implantación de ±0,15 m, pendiente de CAD; no constituye una precisión topográfica garantizada. | Cimentación | EST-OF-20260710 · Estructura B201 / p. 5; nota de resistencia de zapatas y vigas de atado | 285.95 | Cimentaciones | Hormigón HA-30 |  |  |  |  | concrete_ha30 | [0.658824,0.658824,0.623529] | 0.94 | 0 | Interpretación visual del material documental; el acabado, tono y parámetros PBR no son una especificación contractual. | Cimentación; BIM · Cimentaciones | El plano general de 2026-07-31 mantiene el edificio de oficinas de 200 m², mientras documentación anterior indica su supresión. Se conserva lo dibujado, pendiente de confirmación de la propiedad y del equipo de diseño. | JH_Trazabilidad - Anchura (m): 0.3; Altura de sección (m): 0.6; Cota superior absoluta (m): 284.95; Simplificación geométrica: Excentricidad de las vigas de atado respecto a los muros simplificada mediante ejes; armaduras no modeladas.; Discrepancia pendiente: No se ha identificado una discrepancia de sección en la documentación revisada.; JH_DimensionesDocumentadas - Cota superior absoluta: 284.95 m; Anchura: 0.3 m; Altura de sección: 0.6 m
Edificio de oficinas · viga de atado VC1 · 4 | Planos de estructura del edificio de oficinas; Planos de estructura del edificio de oficinas | Hormigón armado HA-30 | 9.65 × 0.3 × 0.6 | 284.35 | 284.95 | 1.737 | office_0263 | 1.61157 | 9.60093 | 0.6 | 17.73 | 1.737 | office | Edificio de oficinas | {"name":"Hormigón armado HA-30","source":"EST-OF-20260710 · Estructura B201 / p. 5; nota de resistencia de zapatas y vigas de atado","status":"known"} | {"documented":[{"label":"Cota superior absoluta","value":284.95,"unit":"m","source":"EST-OF-20260710 · Estructura B201 / p. 5","status":"documentado"},{"label":"Anchura","value":0.3,"unit":"m","source":"EST-OF-20260710 · Estructura B201 / p. 5","status":"documentado"},{"label":"Altura de sección","value":0.6,"unit":"m","source":"EST-OF-20260710 · Estructura B201 / p. 5","status":"documentado"}],"geometry":[{"label":"Dimensiones de la caja local del elemento (X, Y, Z)","value":"9.65 × 0.3 × 0.6","unit":"m","source":"Malla triangulada del elemento en ejes locales del edificio","status":"derivado"},{"label":"Cota mínima absoluta de la malla","value":284.35,"unit":"m","source":"Malla de proyecto y origen altimétrico 285 m","status":"derivado"},{"label":"Cota máxima absoluta de la malla","value":284.95,"unit":"m","source":"Malla de proyecto y origen altimétrico 285 m","status":"derivado"},{"label":"Volumen geométrico bruto","value":1.737,"unit":"m³","source":"Malla cerrada del elemento","status":"derivado"}],"notes":["Las dimensiones documentadas proceden de anotaciones o cuadros; la caja y el volumen se calculan a partir de la malla.","El volumen es exclusivamente geométrico y bruto; no representa una medición neta de material ni una cantidad de compra."]} | {"documentId":"EST-OF-20260710","title":"Planos de estructura del edificio de oficinas","date":"2026-07-10","sheet":"Estructura B201 / p. 5"} | derivado | ["El plano general de 2026-07-31 mantiene el edificio de oficinas de 200 m², mientras documentación anterior indica su supresión. Se conserva lo dibujado, pendiente de confirmación de la propiedad y del equipo de diseño.","Excentricidad de las vigas de atado respecto a los muros simplificada mediante ejes; armaduras no modeladas.","Registro de líneas del PDF general, envolvente de 20 × 10 m; eje local 1 al norte y acceso del lado A al oeste. Estimación de trabajo de implantación de ±0,15 m, pendiente de CAD; no constituye una precisión topográfica garantizada."] | {"horizontalStatus":"derivado","verticalStatus":"derivado","baseElevationM":285.95,"note":"Registro de líneas del PDF general, envolvente de 20 × 10 m; eje local 1 al norte y acceso del lado A al oeste. Estimación de trabajo de implantación de ±0,15 m, pendiente de CAD; no constituye una precisión topográfica garantizada."} | {"boundingBoxM":{"min":[24.233115,72.12228,-0.65],"max":[25.844687,81.723212,-0.05]},"extentsM":[1.611572,9.600932,0.6],"meshSurfaceM2":17.729997,"meshVolumeM3":1.736999,"closedSolid":true,"basis":"Geometría triangulada releída del IFC; envolventes y magnitudes no contractuales."} | {"material":true,"document":true,"quantities":true,"containerGuid":"3ztlotcerHPueDgxP84R6z","containerName":"Planta baja"} | {"id":"foundations","name":"Cimentaciones"} | {"profileId":"concrete_ha30","name":"Hormigón HA-30","materialName":"Hormigón armado HA-30","physicalMaterialStatus":"known","physicalMaterialSource":"EST-OF-20260710 · Estructura B201 / p. 5; nota de resistencia de zapatas y vigas de atado","appearanceStatus":"criterio_visual","appearanceBasis":"Interpretación visual del material documental; el acabado, tono y parámetros PBR no son una especificación contractual.","note":"La apariencia gráfica no modifica ni confirma la especificación física del material."} | {"elementId":"office_0263","ifcGuid":"1k7Vrszw5L8fUsUqnDnRof","ifcClass":"IfcBeam","buildingId":"office","buildingName":"Edificio de oficinas","sourceDocumentId":"EST-OF-20260710","sourceRepresentationKind":"documentary_mesh"} | {"layerId":"foundations","layerName":"Cimentaciones","role":"Viga","basis":"Clasificación por función del elemento; no modifica las especificaciones documentales."} | foundations | {"profileId":"concrete_ha30","name":"Hormigón HA-30","status":"criterio_visual","basis":"Interpretación visual del material documental; el acabado, tono y parámetros PBR no son una especificación contractual.","physicalMaterialUnchanged":true} | EST-OF-20260710 · Estructura B201 / p. 5 | Sección y cota superior documentadas en el cuadro y las notas generales; trazado simplificado uniendo los centros de las zapatas. |  |  |  |  |  |  | Registro de líneas del PDF general, envolvente de 20 × 10 m; eje local 1 al norte y acceso del lado A al oeste. Estimación de trabajo de implantación de ±0,15 m, pendiente de CAD; no constituye una precisión topográfica garantizada. | Cimentación | EST-OF-20260710 · Estructura B201 / p. 5; nota de resistencia de zapatas y vigas de atado | 285.95 | Cimentaciones | Hormigón HA-30 |  |  |  |  | concrete_ha30 | [0.658824,0.658824,0.623529] | 0.94 | 0 | Interpretación visual del material documental; el acabado, tono y parámetros PBR no son una especificación contractual. | Cimentación; BIM · Cimentaciones | El plano general de 2026-07-31 mantiene el edificio de oficinas de 200 m², mientras documentación anterior indica su supresión. Se conserva lo dibujado, pendiente de confirmación de la propiedad y del equipo de diseño. | JH_Trazabilidad - Anchura (m): 0.3; Altura de sección (m): 0.6; Cota superior absoluta (m): 284.95; Simplificación geométrica: Excentricidad de las vigas de atado respecto a los muros simplificada mediante ejes; armaduras no modeladas.; Discrepancia pendiente: No se ha identificado una discrepancia de sección en la documentación revisada.; JH_DimensionesDocumentadas - Cota superior absoluta: 284.95 m; Anchura: 0.3 m; Altura de sección: 0.6 m
Edificio de oficinas · viga de atado VC1 · 5 | Planos de estructura del edificio de oficinas; Planos de estructura del edificio de oficinas | Hormigón armado HA-30 | 0.3 × 9.21 × 0.6 | 284.35 | 284.95 | 1.6578 | office_0264 | 9.16503 | 1.55164 | 0.6 | 16.938 | 1.6578 | office | Edificio de oficinas | {"name":"Hormigón armado HA-30","source":"EST-OF-20260710 · Estructura B201 / p. 5; nota de resistencia de zapatas y vigas de atado","status":"known"} | {"documented":[{"label":"Cota superior absoluta","value":284.95,"unit":"m","source":"EST-OF-20260710 · Estructura B201 / p. 5","status":"documentado"},{"label":"Anchura","value":0.3,"unit":"m","source":"EST-OF-20260710 · Estructura B201 / p. 5","status":"documentado"},{"label":"Altura de sección","value":0.6,"unit":"m","source":"EST-OF-20260710 · Estructura B201 / p. 5","status":"documentado"}],"geometry":[{"label":"Dimensiones de la caja local del elemento (X, Y, Z)","value":"0.3 × 9.21 × 0.6","unit":"m","source":"Malla triangulada del elemento en ejes locales del edificio","status":"derivado"},{"label":"Cota mínima absoluta de la malla","value":284.35,"unit":"m","source":"Malla de proyecto y origen altimétrico 285 m","status":"derivado"},{"label":"Cota máxima absoluta de la malla","value":284.95,"unit":"m","source":"Malla de proyecto y origen altimétrico 285 m","status":"derivado"},{"label":"Volumen geométrico bruto","value":1.6578,"unit":"m³","source":"Malla cerrada del elemento","status":"derivado"}],"notes":["Las dimensiones documentadas proceden de anotaciones o cuadros; la caja y el volumen se calculan a partir de la malla.","El volumen es exclusivamente geométrico y bruto; no representa una medición neta de material ni una cantidad de compra."]} | {"documentId":"EST-OF-20260710","title":"Planos de estructura del edificio de oficinas","date":"2026-07-10","sheet":"Estructura B201 / p. 5"} | derivado | ["El plano general de 2026-07-31 mantiene el edificio de oficinas de 200 m², mientras documentación anterior indica su supresión. Se conserva lo dibujado, pendiente de confirmación de la propiedad y del equipo de diseño.","Excentricidad de las vigas de atado respecto a los muros simplificada mediante ejes; armaduras no modeladas.","Registro de líneas del PDF general, envolvente de 20 × 10 m; eje local 1 al norte y acceso del lado A al oeste. Estimación de trabajo de implantación de ±0,15 m, pendiente de CAD; no constituye una precisión topográfica garantizada."] | {"horizontalStatus":"derivado","verticalStatus":"derivado","baseElevationM":285.95,"note":"Registro de líneas del PDF general, envolvente de 20 × 10 m; eje local 1 al norte y acceso del lado A al oeste. Estimación de trabajo de implantación de ±0,15 m, pendiente de CAD; no constituye una precisión topográfica garantizada."} | {"boundingBoxM":{"min":[17.865852,91.114249,-0.65],"max":[27.030884,92.665891,-0.05]},"extentsM":[9.165032,1.551642,0.6],"meshSurfaceM2":16.937996,"meshVolumeM3":1.657799,"closedSolid":true,"basis":"Geometría triangulada releída del IFC; envolventes y magnitudes no contractuales."} | {"material":true,"document":true,"quantities":true,"containerGuid":"3ztlotcerHPueDgxP84R6z","containerName":"Planta baja"} | {"id":"foundations","name":"Cimentaciones"} | {"profileId":"concrete_ha30","name":"Hormigón HA-30","materialName":"Hormigón armado HA-30","physicalMaterialStatus":"known","physicalMaterialSource":"EST-OF-20260710 · Estructura B201 / p. 5; nota de resistencia de zapatas y vigas de atado","appearanceStatus":"criterio_visual","appearanceBasis":"Interpretación visual del material documental; el acabado, tono y parámetros PBR no son una especificación contractual.","note":"La apariencia gráfica no modifica ni confirma la especificación física del material."} | {"elementId":"office_0264","ifcGuid":"3_p8KyUNbVKg4SpojEUUFE","ifcClass":"IfcBeam","buildingId":"office","buildingName":"Edificio de oficinas","sourceDocumentId":"EST-OF-20260710","sourceRepresentationKind":"documentary_mesh"} | {"layerId":"foundations","layerName":"Cimentaciones","role":"Viga","basis":"Clasificación por función del elemento; no modifica las especificaciones documentales."} | foundations | {"profileId":"concrete_ha30","name":"Hormigón HA-30","status":"criterio_visual","basis":"Interpretación visual del material documental; el acabado, tono y parámetros PBR no son una especificación contractual.","physicalMaterialUnchanged":true} | EST-OF-20260710 · Estructura B201 / p. 5 | Sección y cota superior documentadas en el cuadro y las notas generales; trazado simplificado uniendo los centros de las zapatas. |  |  |  |  |  |  | Registro de líneas del PDF general, envolvente de 20 × 10 m; eje local 1 al norte y acceso del lado A al oeste. Estimación de trabajo de implantación de ±0,15 m, pendiente de CAD; no constituye una precisión topográfica garantizada. | Cimentación | EST-OF-20260710 · Estructura B201 / p. 5; nota de resistencia de zapatas y vigas de atado | 285.95 | Cimentaciones | Hormigón HA-30 |  |  |  |  | concrete_ha30 | [0.658824,0.658824,0.623529] | 0.94 | 0 | Interpretación visual del material documental; el acabado, tono y parámetros PBR no son una especificación contractual. | Cimentación; BIM · Cimentaciones | El plano general de 2026-07-31 mantiene el edificio de oficinas de 200 m², mientras documentación anterior indica su supresión. Se conserva lo dibujado, pendiente de confirmación de la propiedad y del equipo de diseño. | JH_Trazabilidad - Anchura (m): 0.3; Altura de sección (m): 0.6; Cota superior absoluta (m): 284.95; Simplificación geométrica: Excentricidad de las vigas de atado respecto a los muros simplificada mediante ejes; armaduras no modeladas.; Discrepancia pendiente: No se ha identificado una discrepancia de sección en la documentación revisada.; JH_DimensionesDocumentadas - Cota superior absoluta: 284.95 m; Anchura: 0.3 m; Altura de sección: 0.6 m
Edificio de oficinas · viga de atado VC1 · 6 | Planos de estructura del edificio de oficinas; Planos de estructura del edificio de oficinas | Hormigón armado HA-30 | 0.3 × 9.21 × 0.6 | 284.35 | 284.95 | 1.6578 | office_0265 | 9.16503 | 1.55164 | 0.6 | 16.938 | 1.6578 | office | Edificio de oficinas | {"name":"Hormigón armado HA-30","source":"EST-OF-20260710 · Estructura B201 / p. 5; nota de resistencia de zapatas y vigas de atado","status":"known"} | {"documented":[{"label":"Cota superior absoluta","value":284.95,"unit":"m","source":"EST-OF-20260710 · Estructura B201 / p. 5","status":"documentado"},{"label":"Anchura","value":0.3,"unit":"m","source":"EST-OF-20260710 · Estructura B201 / p. 5","status":"documentado"},{"label":"Altura de sección","value":0.6,"unit":"m","source":"EST-OF-20260710 · Estructura B201 / p. 5","status":"documentado"}],"geometry":[{"label":"Dimensiones de la caja local del elemento (X, Y, Z)","value":"0.3 × 9.21 × 0.6","unit":"m","source":"Malla triangulada del elemento en ejes locales del edificio","status":"derivado"},{"label":"Cota mínima absoluta de la malla","value":284.35,"unit":"m","source":"Malla de proyecto y origen altimétrico 285 m","status":"derivado"},{"label":"Cota máxima absoluta de la malla","value":284.95,"unit":"m","source":"Malla de proyecto y origen altimétrico 285 m","status":"derivado"},{"label":"Volumen geométrico bruto","value":1.6578,"unit":"m³","source":"Malla cerrada del elemento","status":"derivado"}],"notes":["Las dimensiones documentadas proceden de anotaciones o cuadros; la caja y el volumen se calculan a partir de la malla.","El volumen es exclusivamente geométrico y bruto; no representa una medición neta de material ni una cantidad de compra."]} | {"documentId":"EST-OF-20260710","title":"Planos de estructura del edificio de oficinas","date":"2026-07-10","sheet":"Estructura B201 / p. 5"} | derivado | ["El plano general de 2026-07-31 mantiene el edificio de oficinas de 200 m², mientras documentación anterior indica su supresión. Se conserva lo dibujado, pendiente de confirmación de la propiedad y del equipo de diseño.","Excentricidad de las vigas de atado respecto a los muros simplificada mediante ejes; armaduras no modeladas.","Registro de líneas del PDF general, envolvente de 20 × 10 m; eje local 1 al norte y acceso del lado A al oeste. Estimación de trabajo de implantación de ±0,15 m, pendiente de CAD; no constituye una precisión topográfica garantizada."] | {"horizontalStatus":"derivado","verticalStatus":"derivado","baseElevationM":285.95,"note":"Registro de líneas del PDF general, envolvente de 20 × 10 m; eje local 1 al norte y acceso del lado A al oeste. Estimación de trabajo de implantación de ±0,15 m, pendiente de CAD; no constituye una precisión topográfica garantizada."} | {"boundingBoxM":{"min":[15.237116,71.994109,-0.65],"max":[24.402148,73.545751,-0.05]},"extentsM":[9.165032,1.551642,0.6],"meshSurfaceM2":16.937996,"meshVolumeM3":1.657799,"closedSolid":true,"basis":"Geometría triangulada releída del IFC; envolventes y magnitudes no contractuales."} | {"material":true,"document":true,"quantities":true,"containerGuid":"3ztlotcerHPueDgxP84R6z","containerName":"Planta baja"} | {"id":"foundations","name":"Cimentaciones"} | {"profileId":"concrete_ha30","name":"Hormigón HA-30","materialName":"Hormigón armado HA-30","physicalMaterialStatus":"known","physicalMaterialSource":"EST-OF-20260710 · Estructura B201 / p. 5; nota de resistencia de zapatas y vigas de atado","appearanceStatus":"criterio_visual","appearanceBasis":"Interpretación visual del material documental; el acabado, tono y parámetros PBR no son una especificación contractual.","note":"La apariencia gráfica no modifica ni confirma la especificación física del material."} | {"elementId":"office_0265","ifcGuid":"067jWOIlfHQQpy5RUT5xE$","ifcClass":"IfcBeam","buildingId":"office","buildingName":"Edificio de oficinas","sourceDocumentId":"EST-OF-20260710","sourceRepresentationKind":"documentary_mesh"} | {"layerId":"foundations","layerName":"Cimentaciones","role":"Viga","basis":"Clasificación por función del elemento; no modifica las especificaciones documentales."} | foundations | {"profileId":"concrete_ha30","name":"Hormigón HA-30","status":"criterio_visual","basis":"Interpretación visual del material documental; el acabado, tono y parámetros PBR no son una especificación contractual.","physicalMaterialUnchanged":true} | EST-OF-20260710 · Estructura B201 / p. 5 | Sección y cota superior documentadas en el cuadro y las notas generales; trazado simplificado uniendo los centros de las zapatas. |  |  |  |  |  |  | Registro de líneas del PDF general, envolvente de 20 × 10 m; eje local 1 al norte y acceso del lado A al oeste. Estimación de trabajo de implantación de ±0,15 m, pendiente de CAD; no constituye una precisión topográfica garantizada. | Cimentación | EST-OF-20260710 · Estructura B201 / p. 5; nota de resistencia de zapatas y vigas de atado | 285.95 | Cimentaciones | Hormigón HA-30 |  |  |  |  | concrete_ha30 | [0.658824,0.658824,0.623529] | 0.94 | 0 | Interpretación visual del material documental; el acabado, tono y parámetros PBR no son una especificación contractual. | Cimentación; BIM · Cimentaciones | El plano general de 2026-07-31 mantiene el edificio de oficinas de 200 m², mientras documentación anterior indica su supresión. Se conserva lo dibujado, pendiente de confirmación de la propiedad y del equipo de diseño. | JH_Trazabilidad - Anchura (m): 0.3; Altura de sección (m): 0.6; Cota superior absoluta (m): 284.95; Simplificación geométrica: Excentricidad de las vigas de atado respecto a los muros simplificada mediante ejes; armaduras no modeladas.; Discrepancia pendiente: No se ha identificado una discrepancia de sección en la documentación revisada.; JH_DimensionesDocumentadas - Cota superior absoluta: 284.95 m; Anchura: 0.3 m; Altura de sección: 0.6 m

# IfcBeam: Cimentación industrial (4)
In: Parcela industrial Jinhong
Description: Cimentación industrial; PredefinedType: USERDEFINED; Document: Cimentaciones de equipos y pedestales del fabricante · revisión recibida 04/09/2026; Group: Zona de separación de aire; BIM · Cimentaciones
JH_DimensionesDelModelo - Extensión de la malla en Z: 0.28 m; Cota inferior de visualización: 287.2 m; Cota superior de visualización: 287.48 m
JH_MagnitudesGeometricas - ExtensionZ: 0.28 m
JH_InformacionBIM - material: {"name":"Hormigón armado · clase pendiente de confirmar","status":"Clase no confirmada en la hoja de equipo","source":"Geometría de cimentación del fabricante; no se extrapola HA-30 de la nota de pedestales."}; status: provisional; issues: ["La planta general y algunos croquis de apoyo muestran dimensiones transversales distintas. Se usan el contorno de cimentación y los centros de pilares de la implantación general; sección de viga VC1 400 × 400 mm y vuelo a 1050 mm del eje según detalle.","La capa de mortero sobre la losa no tiene una referencia vertical inequívoca; no se duplica una capa independiente en esa losa."]; positioning: {"Cota inferior relativa (m)":1.1,"Cota superior relativa (m)":1.38,"Cero absoluto de visualización (m)":286.1,"Estado del cero absoluto":"Provisional","Criterio":"Las cotas relativas proceden del dibujo; la equivalencia absoluta no está confirmada."}; supportPositionIds: []; buildingId: process_plant; buildingName: Zona de separación de aire; category: Cimentación industrial; representationKind: foundation; geometryStatus: Geometría de fabricante; implantación absoluta provisional; ifcClass: IfcBeam; visualLayer: {"id":"foundations","name":"Cimentaciones"}; materialAppearance: {"profileId":"concrete_reinforced","name":"Hormigón armado · gris natural","materialName":"Hormigón armado · clase pendiente de confirmar","physicalMaterialStatus":"Clase no confirmada en la hoja de equipo","physicalMaterialSource":"Geometría de cimentación del fabricante; no se extrapola HA-30 de la nota de pedestales.","appearanceStatus":"criterio_visual","appearanceBasis":"Interpretación visual del material documental; el acabado, tono y parámetros PBR no son una especificación contractual.","note":"La apariencia gráfica no modifica ni confirma la especificación física del material."}; componentSeparation: {"status":"objeto_independiente","note":"Control de visibilidad del objeto completo; la clasificación no altera la malla."}; classification: {"layerId":"foundations","layerName":"Cimentaciones","role":"Cimentación industrial","basis":"Clasificación por función del elemento; no modifica las especificaciones documentales."}; layerId: foundations; appearance: {"profileId":"concrete_reinforced","name":"Hormigón armado · gris natural","status":"criterio_visual","basis":"Interpretación visual del material documental; el acabado, tono y parámetros PBR no son una especificación contractual.","physicalMaterialUnchanged":true}
JH_Trazabilidad - Documento de origen: Cimentaciones de equipos y pedestales del fabricante · revisión recibida 04/09/2026; Material: Hormigón armado · clase pendiente de confirmar; Cota inferior relativa (m): 1.1; Cota superior relativa (m): 1.38; Espesor o altura real de sección (m): 0.28; Referencia vertical: Cotas relativas del dibujo. La equivalencia con un datum absoluto está pendiente.; Implantación para visualización: Z del modelo = cota relativa + 1,10 m. Correspondencia provisional con 286,10 m; no es cota de obra confirmada.; Estado de la geometría: Sección y contornos del fabricante; incidencias conservadas; Incidencias de origen: La planta general y algunos croquis de apoyo muestran dimensiones transversales distintas. Se usan el contorno de cimentación y los centros de pilares de la implantación general; sección de viga VC1 400 × 400 mm y vuelo a 1050 mm del eje según detalle. | La capa de mortero sobre la losa no tiene una referencia vertical inequívoca; no se duplica una capa independiente en esa losa.; Capa BIM: Cimentaciones; Acabado de visualización: Hormigón armado · gris natural; Estado del acabado: criterio_visual; Categoria: Cimentación industrial; ClaseIFC: IfcBeam; EstadoDeInformacion: provisional; IncidenciasPendientes: ["La planta general y algunos croquis de apoyo muestran dimensiones transversales distintas. Se usan el contorno de cimentación y los centros de pilares de la implantación general; sección de viga VC1 400 × 400 mm y vuelo a 1050 mm del eje según detalle.","La capa de mortero sobre la losa no tiene una referencia vertical inequívoca; no se duplica una capa independiente en esa losa."]; UsoDeLasMagnitudes: Geometría de coordinación. Los volúmenes de referencia y subcomponentes no son cantidades de material ni componentes de fabricación certificados.
JH_CriterioDePosicion - PosicionYEstado: {"Cota inferior relativa (m)":1.1,"Cota superior relativa (m)":1.38,"Cero absoluto de visualización (m)":286.1,"Estado del cero absoluto":"Provisional","Criterio":"Las cotas relativas proceden del dibujo; la equivalencia absoluta no está confirmada."}
JH_EvidenciaDeMaterial - name: Hormigón armado · clase pendiente de confirmar; status: Clase no confirmada en la hoja de equipo; source: Geometría de cimentación del fabricante; no se extrapola HA-30 de la nota de pedestales.
JH_DimensionesDocumentadas - Cota inferior relativa adoptada: 1.1 m; Cota superior relativa adoptada: 1.38 m
JH_CapaBIM - IdentificadorCapa: foundations; NombreCapa: Cimentaciones; Funcion: Cimentación industrial; VisibilidadInicial: yes
JH_AcabadoVisual - Perfil: concrete_reinforced; Acabado: Hormigón armado · gris natural; ColorRGB: [0.666667,0.662745,0.619608]; Rugosidad: 0.96; Metallicidad: 0; Estado: criterio_visual; Referencia: Interpretación visual del material documental; el acabado, tono y parámetros PBR no son una especificación contractual.; Nota: La apariencia no certifica el material físico ni el acabado de fabricación.
Name | Extensión de la malla en X (m) = ExtensionX (m) | Extensión de la malla en Y (m) = ExtensionY (m) | SuperficieDeLaMalla (m2) | VolumenGeometrico (m3) = Volumen geométrico (m³) | source = DocumentoFuente | dimensions | assemblyId = Conjunto de cimentación | equipmentIds | sectionRef = Sección de referencia | sourceCadHandles | stableElementKey | geometryMetrics | visualizationIdentity | Equipos asociados | Identificadores CAD de referencia | Área de planta (m²) | Identificador | Extensión local X (m) | Extensión local Y (m)
Cimentación y plataforma del módulo LV-CONTAINER · vigas perimetrales VC1 400 × 400 mm | 4.531 | 9.27334 | 31.144 | 2.5648 | {"documentId":"LHD2609-JG00100-20260904","title":"Cimentaciones de equipos y pedestales del fabricante · revisión recibida 04/09/2026","date":"2026-09-04","sheet":"13–13","fileName":"LHD2609-JG00100_20260904.dwg","revisionCaveat":"Fecha de revisión tomada del nombre recibido; cajetines internos mantienen 02/07/2026 y algunos textos de plantilla.","sourceFileSha256":"b42eb027b7bc0b14c38d1d13514f4899b58a732aa8d0ba2ccf10fa2fc3192890"} | {"documented":[{"label":"Extensión local X","value":3.35,"unit":"m","source":"55EB/55F1, 1DB82, 1DE55","status":"derivada del contorno CAD"},{"label":"Extensión local Y","value":8.9,"unit":"m","source":"55EB/55F1, 1DB82, 1DE55","status":"derivada del contorno CAD"},{"label":"Cota inferior relativa adoptada","value":1.1,"unit":"m","source":"13–13","status":"interpretación con conflicto conservado"},{"label":"Cota superior relativa adoptada","value":1.38,"unit":"m","source":"13–13","status":"documentada / separación por material"}],"geometry":[{"label":"Extensión de la malla en X","value":4.530995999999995,"unit":"m","source":"Geometría releída del IFC; datum absoluto de proceso provisional","status":"derivado"},{"label":"Extensión de la malla en Y","value":9.273342,"unit":"m","source":"Geometría releída del IFC; datum absoluto de proceso provisional","status":"derivado"},{"label":"Extensión de la malla en Z","value":0.2799999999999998,"unit":"m","source":"Geometría releída del IFC; datum absoluto de proceso provisional","status":"derivado"},{"label":"Cota inferior de visualización","value":287.2,"unit":"m","source":"Geometría releída del IFC; datum absoluto de proceso provisional","status":"derivado"},{"label":"Cota superior de visualización","value":287.48,"unit":"m","source":"Geometría releída del IFC; datum absoluto de proceso provisional","status":"derivado"}]} | F-LV-CONTAINER | ["LV-CONTAINER"] | 13–13 | ["55EB/55F1","1DB82","1DE55"] | F-LV-CONTAINER/Cimentación y plataforma del módulo LV-CONTAINER · vigas perimetrales VC1 400 × 400 mm | {"boundingBoxM":{"min":[39.383101,72.82824,2.2],"max":[43.914097,82.101582,2.48]},"extentsM":[4.530996,9.273342,0.28],"meshSurfaceM2":31.144006,"meshVolumeM3":2.564801,"closedSolid":true,"basis":"Magnitudes de las mallas representadas, no cantidades certificadas de obra, compra o fabricación. Las partes pueden compartir superficies; no se suman como un despiece de materiales."} | {"elementId":"found_0904_56c01f6ad420ae","ifcGuid":"3UQ8xliV5UBhHz76QAUS8n","ifcClass":"IfcBeam","buildingId":"process_plant","buildingName":"Zona de separación de aire","sourceDocumentId":"LHD2609-JG00100-20260904","sourceRepresentationKind":"foundation"} | LV-CONTAINER | 55EB/55F1, 1DB82, 1DE55 | 9.16 | found_0904_56c01f6ad420ae | 3.35 | 8.9
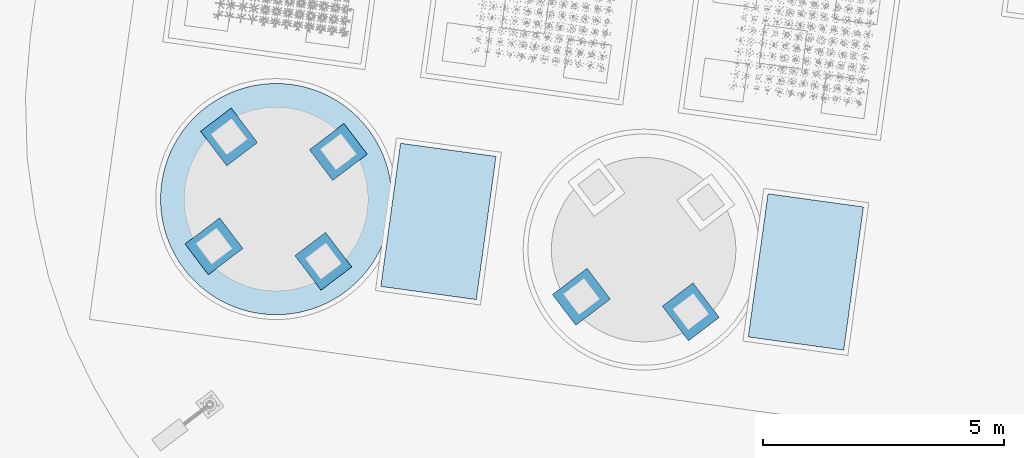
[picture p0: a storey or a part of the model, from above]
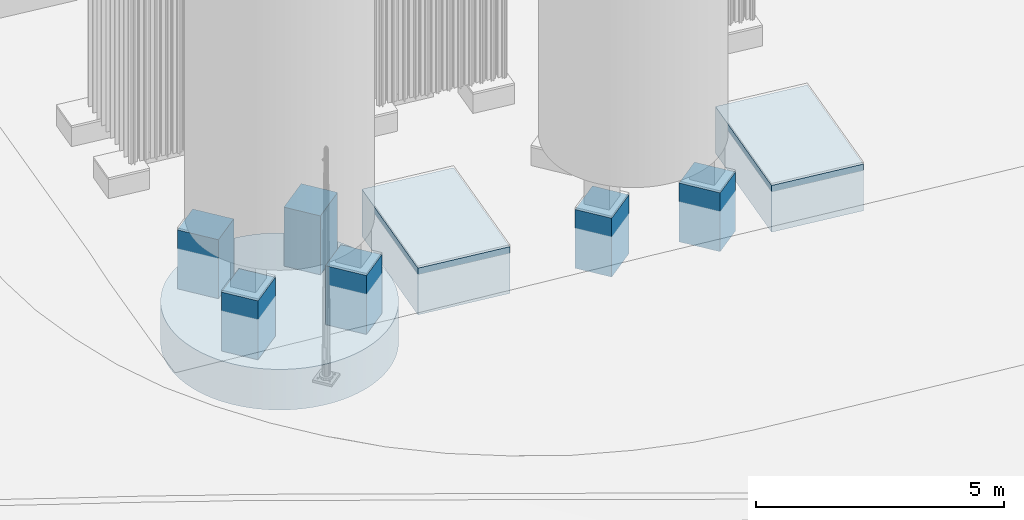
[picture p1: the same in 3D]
Properties of the parts of a building model (IFC4), part 4 of 134

# IfcBeam: Cimentación industrial (4)
Name | Extensión de la malla en X (m) = ExtensionX (m) | Extensión de la malla en Y (m) = ExtensionY (m) | SuperficieDeLaMalla (m2) | VolumenGeometrico (m3) = Volumen geométrico (m³) | source = DocumentoFuente | dimensions | assemblyId = Conjunto de cimentación | equipmentIds | sectionRef = Sección de referencia | sourceCadHandles | stableElementKey | geometryMetrics | visualizationIdentity | Equipos asociados | Identificadores CAD de referencia | Área de planta (m²) | Identificador | Extensión local X (m) | Extensión local Y (m)
Cimentación y plataforma del módulo HV-CONTAINER · vigas perimetrales VC1 400 × 400 mm | 10.0164 | 4.63315 | 33.184 | 2.7328 | {"documentId":"LHD2609-JG00100-20260904","title":"Cimentaciones de equipos y pedestales del fabricante · revisión recibida 04/09/2026","date":"2026-09-04","sheet":"14–14","fileName":"LHD2609-JG00100_20260904.dwg","revisionCaveat":"Fecha de revisión tomada del nombre recibido; cajetines internos mantienen 02/07/2026 y algunos textos de plantilla.","sourceFileSha256":"b42eb027b7bc0b14c38d1d13514f4899b58a732aa8d0ba2ccf10fa2fc3192890"} | {"documented":[{"label":"Extensión local X","value":9.65,"unit":"m","source":"553E/5544, 1DB82, 1DE55","status":"derivada del contorno CAD"},{"label":"Extensión local Y","value":3.35,"unit":"m","source":"553E/5544, 1DB82, 1DE55","status":"derivada del contorno CAD"},{"label":"Cota inferior relativa adoptada","value":1.1,"unit":"m","source":"14–14","status":"interpretación con conflicto conservado"},{"label":"Cota superior relativa adoptada","value":1.38,"unit":"m","source":"14–14","status":"documentada / separación por material"}],"geometry":[{"label":"Extensión de la malla en X","value":10.016353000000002,"unit":"m","source":"Geometría releída del IFC; datum absoluto de proceso provisional","status":"derivado"},{"label":"Extensión de la malla en Y","value":4.633148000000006,"unit":"m","source":"Geometría releída del IFC; datum absoluto de proceso provisional","status":"derivado"},{"label":"Extensión de la malla en Z","value":0.2799999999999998,"unit":"m","source":"Geometría releída del IFC; datum absoluto de proceso provisional","status":"derivado"},{"label":"Cota inferior de visualización","value":287.2,"unit":"m","source":"Geometría releída del IFC; datum absoluto de proceso provisional","status":"derivado"},{"label":"Cota superior de visualización","value":287.48,"unit":"m","source":"Geometría releída del IFC; datum absoluto de proceso provisional","status":"derivado"}]} | F-HV-CONTAINER | ["HV-CONTAINER"] | 14–14 | ["553E/5544","1DB82","1DE55"] | F-HV-CONTAINER/Cimentación y plataforma del módulo HV-CONTAINER · vigas perimetrales VC1 400 × 400 mm | {"boundingBoxM":{"min":[54.914059,78.843835,2.2],"max":[64.930412,83.476983,2.48]},"extentsM":[10.016353,4.633148,0.28],"meshSurfaceM2":33.183989,"meshVolumeM3":2.732799,"closedSolid":true,"basis":"Magnitudes de las mallas representadas, no cantidades certificadas de obra, compra o fabricación. Las partes pueden compartir superficies; no se suman como un despiece de materiales."} | {"elementId":"found_0904_b2e389c2d6a507","ifcGuid":"3XKy$zqP9TWQD_1M85WkIU","ifcClass":"IfcBeam","buildingId":"process_plant","buildingName":"Zona de separación de aire","sourceDocumentId":"LHD2609-JG00100-20260904","sourceRepresentationKind":"foundation"} | HV-CONTAINER | 553E/5544, 1DB82, 1DE55 | 9.76 | found_0904_b2e389c2d6a507 | 9.65 | 3.35
Cimentación y plataforma del módulo IC-CONTAINER · vigas perimetrales VC1 400 × 400 mm | 4.72849 | 10.7098 | 35.088 | 2.8896 | {"documentId":"LHD2609-JG00100-20260904","title":"Cimentaciones de equipos y pedestales del fabricante · revisión recibida 04/09/2026","date":"2026-09-04","sheet":"15–15","fileName":"LHD2609-JG00100_20260904.dwg","revisionCaveat":"Fecha de revisión tomada del nombre recibido; cajetines internos mantienen 02/07/2026 y algunos textos de plantilla.","sourceFileSha256":"b42eb027b7bc0b14c38d1d13514f4899b58a732aa8d0ba2ccf10fa2fc3192890"} | {"documented":[{"label":"Extensión local X","value":3.35,"unit":"m","source":"5645/5652, 1DB82, 1DE55","status":"derivada del contorno CAD"},{"label":"Extensión local Y","value":10.35,"unit":"m","source":"5645/5652, 1DB82, 1DE55","status":"derivada del contorno CAD"},{"label":"Cota inferior relativa adoptada","value":1.1,"unit":"m","source":"15–15","status":"interpretación con conflicto conservado"},{"label":"Cota superior relativa adoptada","value":1.38,"unit":"m","source":"15–15","status":"documentada / separación por material"}],"geometry":[{"label":"Extensión de la malla en X","value":4.728490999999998,"unit":"m","source":"Geometría releída del IFC; datum absoluto de proceso provisional","status":"derivado"},{"label":"Extensión de la malla en Y","value":10.709830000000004,"unit":"m","source":"Geometría releída del IFC; datum absoluto de proceso provisional","status":"derivado"},{"label":"Extensión de la malla en Z","value":0.2799999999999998,"unit":"m","source":"Geometría releída del IFC; datum absoluto de proceso provisional","status":"derivado"},{"label":"Cota inferior de visualización","value":287.2,"unit":"m","source":"Geometría releída del IFC; datum absoluto de proceso provisional","status":"derivado"},{"label":"Cota superior de visualización","value":287.48,"unit":"m","source":"Geometría releída del IFC; datum absoluto de proceso provisional","status":"derivado"}]} | F-IC-CONTAINER | ["IC-CONTAINER"] | 15–15 | ["5645/5652","1DB82","1DE55"] | F-IC-CONTAINER/Cimentación y plataforma del módulo IC-CONTAINER · vigas perimetrales VC1 400 × 400 mm | {"boundingBoxM":{"min":[37.847402,61.658313,2.2],"max":[42.575893,72.368143,2.48]},"extentsM":[4.728491,10.70983,0.28],"meshSurfaceM2":35.088007,"meshVolumeM3":2.889601,"closedSolid":true,"basis":"Magnitudes de las mallas representadas, no cantidades certificadas de obra, compra o fabricación. Las partes pueden compartir superficies; no se suman como un despiece de materiales."} | {"elementId":"found_0904_57c4e0ee32d3f7","ifcGuid":"0kOXe7aLrTnxWd8wShF1Zk","ifcClass":"IfcBeam","buildingId":"process_plant","buildingName":"Zona de separación de aire","sourceDocumentId":"LHD2609-JG00100-20260904","sourceRepresentationKind":"foundation"} | IC-CONTAINER | 5645/5652, 1DB82, 1DE55 | 10.32 | found_0904_57c4e0ee32d3f7 | 3.35 | 10.35
Cimentación y plataforma del módulo MV-CONTAINER · vigas perimetrales VC1 400 × 400 mm | 7.53965 | 4.29264 | 26.384 | 2.1728 | {"documentId":"LHD2609-JG00100-20260904","title":"Cimentaciones de equipos y pedestales del fabricante · revisión recibida 04/09/2026","date":"2026-09-04","sheet":"16–16","fileName":"LHD2609-JG00100_20260904.dwg","revisionCaveat":"Fecha de revisión tomada del nombre recibido; cajetines internos mantienen 02/07/2026 y algunos textos de plantilla.","sourceFileSha256":"b42eb027b7bc0b14c38d1d13514f4899b58a732aa8d0ba2ccf10fa2fc3192890"} | {"documented":[{"label":"Extensión local X","value":7.15,"unit":"m","source":"5599/559F, 1DB82, 1DE55","status":"derivada del contorno CAD"},{"label":"Extensión local Y","value":3.35,"unit":"m","source":"5599/559F, 1DB82, 1DE55","status":"derivada del contorno CAD"},{"label":"Cota inferior relativa adoptada","value":1.1,"unit":"m","source":"16–16","status":"interpretación con conflicto conservado"},{"label":"Cota superior relativa adoptada","value":1.38,"unit":"m","source":"16–16","status":"documentada / separación por material"}],"geometry":[{"label":"Extensión de la malla en X","value":7.539650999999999,"unit":"m","source":"Geometría releída del IFC; datum absoluto de proceso provisional","status":"derivado"},{"label":"Extensión de la malla en Y","value":4.292638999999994,"unit":"m","source":"Geometría releída del IFC; datum absoluto de proceso provisional","status":"derivado"},{"label":"Extensión de la malla en Z","value":0.2799999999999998,"unit":"m","source":"Geometría releída del IFC; datum absoluto de proceso provisional","status":"derivado"},{"label":"Cota inferior de visualización","value":287.2,"unit":"m","source":"Geometría releída del IFC; datum absoluto de proceso provisional","status":"derivado"},{"label":"Cota superior de visualización","value":287.48,"unit":"m","source":"Geometría releída del IFC; datum absoluto de proceso provisional","status":"derivado"}]} | F-MV-CONTAINER | ["MV-CONTAINER"] | 16–16 | ["5599/559F","1DB82","1DE55"] | F-MV-CONTAINER/Cimentación y plataforma del módulo MV-CONTAINER · vigas perimetrales VC1 400 × 400 mm | {"boundingBoxM":{"min":[46.889049,80.287664,2.2],"max":[54.4287,84.580303,2.48]},"extentsM":[7.539651,4.292639,0.28],"meshSurfaceM2":26.384006,"meshVolumeM3":2.172801,"closedSolid":true,"basis":"Magnitudes de las mallas representadas, no cantidades certificadas de obra, compra o fabricación. Las partes pueden compartir superficies; no se suman como un despiece de materiales."} | {"elementId":"found_0904_ee7d9428005826","ifcGuid":"28jk9scxjNHPVJyIWDGtHU","ifcClass":"IfcBeam","buildingId":"process_plant","buildingName":"Zona de separación de aire","sourceDocumentId":"LHD2609-JG00100-20260904","sourceRepresentationKind":"foundation"} | MV-CONTAINER | 5599/559F, 1DB82, 1DE55 | 7.76 | found_0904_ee7d9428005826 | 7.15 | 3.35

# IfcBuildingElementProxy (140)
In: Parcela industrial Jinhong
JH_InformacionBIM - buildingId: process_plant; buildingName: Planta de proceso; ifcClass: IfcBuildingElementProxy; status: provisional
JH_Trazabilidad - Clase IFC: IfcBuildingElementProxy; ClaseIFC: IfcBuildingElementProxy; EstadoDeInformacion: provisional
JH_EvidenciaDeMaterial - name: No especificado; status: unknown
Name | Description | Document | Extensión de la malla en X (m) = ExtensionX (m) | Extensión de la malla en Y (m) = ExtensionY (m) | Extensión de la malla en Z (m) = ExtensionZ (m) | Cota inferior de visualización (m) | Cota superior de visualización (m) | SuperficieDeLaMalla (m2) | VolumenGeometrico (m3) | level | category = Categoria = Funcion | representationKind | material | dimensions | JH_InformacionBIM, source = DocumentoFuente | positioning = PosicionYEstado | issues | detailGeometry | geometryMetrics | installationSource | layerId = IdentificadorCapa | visualLayer | materialAppearance | componentSeparation | visualizationIdentity | classification | appearance | Disciplina | Material | Capa BIM = NombreCapa | Acabado de visualización = Acabado | Estado del acabado = Estado | Identificador | JH_Trazabilidad, IncidenciasPendientes | UsoDeLasMagnitudes | JH_EvidenciaDeMaterial, source | JH_DetalleGeometrico, source | VisibilidadInicial | Perfil | ColorRGB | Rugosidad | Metallicidad | Referencia | Nota | Group | parentEquipmentId = Identificador del equipo padre | parentEquipmentName = Equipo padre | parentEquipmentIfcClass | parentEquipmentDimensions | parentEquipmentPositioning | parentEquipmentIssues | parentEquipmentDetail | componentRole = Rol del componente | assemblyBBox | assemblyGeometryMetrics | manufacturerDetailsPending | component | assembly | foundationRelationship | installationSourceScope | Identificador del elemento = sourcePartId | Componente | Capa de visualización | Estado del material | Perfil visual del material | Fuente del componente | Criterio de partición | Criterio de las dimensiones | Relación con cimentaciones | Aplicabilidad de las mediciones | Referencia dimensional del conjunto | sourceHandles | partCount | partsAreBOM | status
Bastidor del grupo de válvulas PPU · referencia en planta | Equipo pendiente de altura; plano fuente conservado | Plano del fabricante: implantación de equipos · referencia E7; Cimentaciones de equipos y pedestales del fabricante · revisión recibida 04/09/2026 | 7.83489 | 3.99195 | 0.1 | 286.2 | 286.3 | 15.9226 | 0.483004 | Apoyo relativo +0.100 m; cero absoluto provisional | Equipo pendiente de altura; plano fuente conservado | sourcePlanReference | {"name":"No especificado","source":"Los contornos revisados no especifican el material del equipo.","status":"unknown"} | {"documented":[{"label":"Longitud exterior del bastidor en planta","value":7.49629,"unit":"m","source":"EQ-IMPLANTACION-20260430 · marco 9C1FF","status":"derivado"},{"label":"Anchura exterior del bastidor en planta","value":2.998869,"unit":"m","source":"EQ-IMPLANTACION-20260430 · marco 9C1FF","status":"derivado"},{"label":"Cota relativa de la superficie de apoyo","value":0.1,"unit":"m","source":"LHD2609-JG00100-20260904 · sección 3 / 3-3 · 28D00, 28D41","status":"documentado"}],"geometry":[{"label":"Extensión de la malla en X","value":7.8348886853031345,"unit":"m","source":"Geometría releída del IFC; datum absoluto de proceso provisional","status":"derivado"},{"label":"Extensión de la malla en Y","value":3.9919458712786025,"unit":"m","source":"Geometría releída del IFC; datum absoluto de proceso provisional","status":"derivado"},{"label":"Extensión de la malla en Z","value":0.10000000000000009,"unit":"m","source":"Geometría releída del IFC; datum absoluto de proceso provisional","status":"derivado"},{"label":"Cota inferior de visualización","value":286.20000000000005,"unit":"m","source":"Geometría releída del IFC; datum absoluto de proceso provisional","status":"derivado"},{"label":"Cota superior de visualización","value":286.3,"unit":"m","source":"Geometría releída del IFC; datum absoluto de proceso provisional","status":"derivado"}],"notes":["Geometría exterior de referencia; los volúmenes no representan cantidades de material, compra o fabricación."]} | {"documentId":"EQ-IMPLANTACION-20260430","title":"Plano del fabricante: implantación de equipos · referencia E7","sheet":"Espacio modelo; referencia E7 en el nombre del archivo","date":"2026-04-30"} | {"Estado de la planta":"Derivado del CAD y del giro de implantación","Nivel relativo del apoyo (m)":0.1,"Estado del nivel relativo":"Documentado en el plano de cimentaciones","Cero absoluto de visualización (m)":286.1,"Estado del cero absoluto":"Provisional","Cota del apoyo de visualización (m)":286.20000000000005,"Desplazamiento aplicado a la malla (m)":0.10000000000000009,"Criterio":"Nivel de apoyo relativo documentado. Se adopta el cero de proceso a 286,10 m solo para visualización; la equivalencia absoluta no está confirmada. No se añade un espesor de montaje sin cota del fabricante."} | ["Se recuperan el marco exterior, cuatro contornos de válvulas y un travesaño del bloque activo del fabricante.","La altura física del bastidor, válvulas y tuberías no está documentada; todos los componentes tienen únicamente 0,10 m de espesor visual.","El bastidor rectangular utiliza los límites exterior e interior medidos; se omiten las pequeñas líneas de inglete del dibujo. La representación no desarrolla tuberías, accesorios ni soportes en 3D.","Cara superior de grout HA-35 de 50 mm a +0,100; hormigón a +0,050.","El cero absoluto de la revisión no está definido; 286,10 m sigue siendo una hipótesis de coordinación.","Se alinea el punto inferior del conjunto del equipo, incluidos los pies ya representados, con la superficie de apoyo terminada; no se añade un espesor de calzos, placa o grout del fabricante no documentado.","El bastidor de válvulas se referencia al mismo plano de apoyo de purificación; su elevación de montaje no está acotada."] | {"source":{"documentId":"EQ-IMPLANTACION-20260430","title":"Plano del fabricante: implantación de equipos · referencia E7","sheet":"Espacio modelo; referencia E7 en el nombre del archivo","date":"2026-04-30"},"cadSource":"equipment_layout.dxf","conversion":"ODA","sourceInsertHandle":"8DD29","limitations":["Se recuperan el marco exterior, cuatro contornos de válvulas y un travesaño del bloque activo del fabricante.","La altura física del bastidor, válvulas y tuberías no está documentada; todos los componentes tienen únicamente 0,10 m de espesor visual.","El bastidor rectangular utiliza los límites exterior e interior medidos; se omiten las pequeñas líneas de inglete del dibujo. La representación no desarrolla tuberías, accesorios ni soportes en 3D."],"planMarkerThicknessM":0.1} | {"boundingBoxM":{"min":[50.261744,57.947536,1.2],"max":[58.096632,61.939482,1.3]},"extentsM":[7.834889,3.991946,0.1],"meshSurfaceM2":15.922617,"meshVolumeM3":0.483004,"closedSolid":true,"basis":"Magnitudes de las mallas representadas, no cantidades certificadas de obra, compra o fabricación. Las partes pueden compartir superficies; no se suman como un despiece de materiales."} | {"documentId":"LHD2609-JG00100-20260904","title":"Cimentaciones y pedestales de equipos · revisión recibida 04/09/2026","date":"2026-09-04","sheet":"3 / 3-3","sourceHandles":["28D00","28D41"]} | references | {"id":"references","name":"Referencias documentales"} | {"profileId":"survey_reference","name":"Referencia documental · ámbar","materialName":"No especificado","physicalMaterialStatus":"unknown","physicalMaterialSource":"Los contornos revisados no especifican el material del equipo.","appearanceStatus":"referencia","appearanceBasis":"Interpretación visual del material documental; el acabado, tono y parámetros PBR no son una especificación contractual.","note":"La apariencia gráfica no modifica ni confirma la especificación física del material."} | {"status":"objeto_independiente","note":"Control de visibilidad del objeto completo; la clasificación no altera la malla."} | {"elementId":"PPU-VALVE-SKID","ifcGuid":"2yOD_IBUzTxe4eeZbHTVvE","ifcClass":"IfcBuildingElementProxy","buildingId":"process_plant","buildingName":"Planta de proceso","sourceDocumentId":"EQ-IMPLANTACION-20260430","sourceRepresentationKind":"planReference"} | {"layerId":"references","layerName":"Referencias documentales","role":"Equipo pendiente de altura; plano fuente conservado","basis":"Clasificación por función del elemento; no modifica las especificaciones documentales."} | {"profileId":"survey_reference","name":"Referencia documental · ámbar","status":"referencia","basis":"Interpretación visual del material documental; el acabado, tono y parámetros PBR no son una especificación contractual.","physicalMaterialUnchanged":true} | Equipos | No especificado | Referencias documentales | Referencia documental · ámbar | referencia | PPU-VALVE-SKID | ["Se recuperan el marco exterior, cuatro contornos de válvulas y un travesaño del bloque activo del fabricante.","La altura física del bastidor, válvulas y tuberías no está documentada; todos los componentes tienen únicamente 0,10 m de espesor visual.","El bastidor rectangular utiliza los límites exterior e interior medidos; se omiten las pequeñas líneas de inglete del dibujo. La representación no desarrolla tuberías, accesorios ni soportes en 3D.","Cara superior de grout HA-35 de 50 mm a +0,100; hormigón a +0,050.","El cero absoluto de la revisión no está definido; 286,10 m sigue siendo una hipótesis de coordinación.","Se alinea el punto inferior del conjunto del equipo, incluidos los pies ya representados, con la superficie de apoyo terminada; no se añade un espesor de calzos, placa o grout del fabricante no documentado.","El bastidor de válvulas se referencia al mismo plano de apoyo de purificación; su elevación de montaje no está acotada."] | Geometría de coordinación. Los volúmenes de referencia y subcomponentes no son cantidades de material ni componentes de fabricación certificados. | Los contornos revisados no especifican el material del equipo. | {"documentId":"EQ-IMPLANTACION-20260430","title":"Plano del fabricante: implantación de equipos · referencia E7","sheet":"Espacio modelo; referencia E7 en el nombre del archivo","date":"2026-04-30"} | no | survey_reference | [0.784314,0.584314,0.282353] | 1 | 0 | Interpretación visual del material documental; el acabado, tono y parámetros PBR no son una especificación contractual. | La apariencia no certifica el material físico ni el acabado de fabricación. | Zona de separación de aire; BIM · Referencias documentales | JH_CoordinacionCimentaciones - ElementosDeCimentacion: ["found_0904_c3bd5e0d38836a","found_0904_a16d8875227a01","found_0904_bc40ce234e571f"]; Relacion: Correspondencia documental; no verifica anclajes ni cotas de montaje.; JH_InformacionBIM - foundationIds: ["found_0904_c3bd5e0d38836a","found_0904_a16d8875227a01","found_0904_bc40ce234e571f"]; heightStatus: unknown; heightReference: {"valueM":null,"sourceSupported":false,"reason":"La planta documenta marco, válvulas y travesaño; no hay una cota verificable de altura del bastidor, válvulas ni tuberías."}; isReferenceOnly: yes; JH_Trazabilidad - Identificador del objeto: PPU-VALVE-SKID; Estado de la información: provisional; Aplicabilidad a mediciones: Geometría exterior de referencia; los volúmenes no representan cantidades de material, compra o fabricación.; Documento de origen: Plano del fabricante: implantación de equipos · referencia E7; Convención de coordenadas: Metros en la plataforma local del fabricante; transformación de implantación aplicada durante la integración.; Grado de definición: Se recuperan el marco exterior, cuatro contornos de válvulas y un travesaño del bloque activo del fabricante.; La altura física del bastidor, válvulas y tuberías no está documentada; todos los componentes tienen únicamente 0,10 m de espesor visual.; El bastidor rectangular utiliza los límites exterior e interior medidos; se omiten las pequeñas líneas de inglete del dibujo. La representación no desarrolla tuberías, accesorios ni soportes en 3D.; Identificadores CAD del contorno (handles): 9C1FA, 9C1FF, 9BF7C, 9BF7F, 9BF84, 9BF87, 9C0DE; Nivel relativo de apoyo documentado (m): 0.1; Fuente del nivel de apoyo: {"documentId":"LHD2609-JG00100-20260904","title":"Cimentaciones y pedestales de equipos · revisión recibida 04/09/2026","date":"2026-09-04","sheet":"3 / 3-3","sourceHandles":["28D00","28D41"]}; Criterio de instalación: Nivel de apoyo relativo documentado. Se adopta el cero de proceso a 286,10 m solo para visualización; la equivalencia absoluta no está confirmada. No se añade un espesor de montaje sin cota del fabricante.; Fase del modelo: Revisión de la zona de separación de aire · septiembre de 2026; Estado de altura: Pendiente de plano del fabricante; Capa: Equipos pendientes de altura; JH_DimensionesDocumentadas - Longitud exterior del bastidor en planta: 7.49629 m; Anchura exterior del bastidor en planta: 2.99887 m; Cota relativa de la superficie de apoyo: 0.1 m; JH_DetalleGeometrico - cadSource: equipment_layout.dxf; conversion: ODA; sourceInsertHandle: 8DD29; limitations: ["Se recuperan el marco exterior, cuatro contornos de válvulas y un travesaño del bloque activo del fabricante.","La altura física del bastidor, válvulas y tuberías no está documentada; todos los componentes tienen únicamente 0,10 m de espesor visual.","El bastidor rectangular utiliza los límites exterior e interior medidos; se omiten las pequeñas líneas de inglete del dibujo. La representación no desarrolla tuberías, accesorios ni soportes en 3D."]; planMarkerThicknessM: 0.1
Plano fuente conservado · Adsorbedor PPU-A / MS1202 | Plano fuente de equipo; capa independiente | Plano del fabricante: implantación de equipos · referencia E7 | 3.7921 | 3.79234 | 0.1 | 286.2 | 286.3 | 24.3363 | 1.12132 | Apoyo relativo +0.100 m; cero absoluto provisional | Plano fuente de equipo; capa independiente | sourcePlanReference | {"name":"No especificado","source":"Los contornos revisados no especifican el material del equipo.","status":"unknown"} | {"documented":[{"label":"Diámetro exterior ajustado al contorno CAD","value":3.630197,"unit":"m","source":"EQ-IMPLANTACION-20260430 · polilínea 9C278","status":"derivado"},{"label":"Error radial máximo del ajuste","value":0.001262,"unit":"m","source":"EQ-IMPLANTACION-20260430 · polilínea 9C278","status":"derivado"},{"label":"Número de huellas de apoyo","value":4,"unit":"ud","source":"EQ-IMPLANTACION-20260430 · 9C279,9C27A,9C27B,9C27C","status":"derivado"},{"label":"Cota relativa de la superficie de apoyo","value":0.1,"unit":"m","source":"LHD2609-JG00100-20260904 · sección 3 / 3-3 · 28D00, 28D41","status":"documentado"}],"geometry":[{"label":"Extensión de la malla en X","value":3.792099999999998,"unit":"m","source":"Geometría releída del IFC; datum absoluto de proceso provisional","status":"derivado"},{"label":"Extensión de la malla en Y","value":3.7923410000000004,"unit":"m","source":"Geometría releída del IFC; datum absoluto de proceso provisional","status":"derivado"},{"label":"Extensión de la malla en Z","value":0.10000000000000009,"unit":"m","source":"Geometría releída del IFC; datum absoluto de proceso provisional","status":"derivado"},{"label":"Cota inferior de visualización","value":286.2,"unit":"m","source":"Geometría releída del IFC; datum absoluto de proceso provisional","status":"derivado"},{"label":"Cota superior de visualización","value":286.3,"unit":"m","source":"Geometría releída del IFC; datum absoluto de proceso provisional","status":"derivado"}],"notes":["Geometría exterior de referencia; los volúmenes no representan cantidades de material, compra o fabricación."]} | {"documentId":"EQ-IMPLANTACION-20260430","title":"Plano del fabricante: implantación de equipos · referencia E7","sheet":"Espacio modelo; referencia E7 en el nombre del archivo","date":"2026-04-30"} | {"Estado de la planta":"Derivado del CAD y del giro de implantación","Nivel relativo del apoyo (m)":0.1,"Estado del nivel relativo":"Documentado en el plano de cimentaciones","Cero absoluto de visualización (m)":286.1,"Estado del cero absoluto":"Provisional","Cota del apoyo de visualización (m)":286.20000000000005,"Desplazamiento aplicado a la malla (m)":0.10000000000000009,"Criterio":"Nivel de apoyo relativo documentado. Se adopta el cero de proceso a 286,10 m solo para visualización; la equivalencia absoluta no está confirmada. No se añade un espesor de montaje sin cota del fabricante."} | ["Copia exacta del plano de referencia previo; no constituye un segundo equipo ni una segunda cimentación.","Espesor de 0,10 m exclusivamente gráfico; mantener esta capa independiente del volumen de referencia."] | {"sourcePlanRetainedFromObject":"PPU-A-PLAN","sourcePlanRetainedFromGuid":"2O$9mJixLME8AOrxnEUH3D","geometryCopy":"Exact vertices and faces from published v4; no added offset."} | {"boundingBoxM":{"min":[48.696299,54.707124,1.2],"max":[52.488399,58.499465,1.3]},"extentsM":[3.7921,3.792341,0.1],"meshSurfaceM2":24.336262,"meshVolumeM3":1.12132,"closedSolid":true,"basis":"Geometría de coordinación. Los volúmenes de referencia y subcomponentes no son cantidades de material ni componentes de fabricación certificados."} | {"documentId":"LHD2609-JG00100-20260904","title":"Cimentaciones y pedestales de equipos · revisión recibida 04/09/2026","date":"2026-09-04","sheet":"3 / 3-3","sourceHandles":["28D00","28D41"]} | references | {"id":"references","name":"Referencias documentales"} | {"profileId":"survey_reference","name":"Referencia documental · ámbar","appearanceStatus":"referencia","appearanceBasis":"Interpretación visual del material documental; el acabado, tono y parámetros PBR no son una especificación contractual."} |  |  | {"layerId":"references","layerName":"Referencias documentales","role":"Plano fuente de equipo; capa independiente","basis":"Clasificación por función del elemento; no modifica las especificaciones documentales."} | {"profileId":"survey_reference","name":"Referencia documental · ámbar","status":"referencia","basis":"Interpretación visual del material documental; el acabado, tono y parámetros PBR no son una especificación contractual.","physicalMaterialUnchanged":true} |  |  | Referencias documentales | Referencia documental · ámbar | referencia | SOURCE-PLAN-PPU-A-PLAN | ["Copia exacta del plano de referencia previo; no constituye un segundo equipo ni una segunda cimentación.","Espesor de 0,10 m exclusivamente gráfico; mantener esta capa independiente del volumen de referencia."] | Geometría de coordinación. Los volúmenes de referencia y subcomponentes no son cantidades de material ni componentes de fabricación certificados. | Los contornos revisados no especifican el material del equipo. |  | no | survey_reference | [0.784314,0.584314,0.282353] | 1 | 0 | Interpretación visual del material documental; el acabado, tono y parámetros PBR no son una especificación contractual. | La apariencia no certifica el material físico ni el acabado de fabricación. | BIM · Referencias documentales | JH_InformacionBIM - foundationIds: []; heightStatus: not_applicable; isReferenceOnly: yes; sourceReferenceOf: PPU-A-PLAN; quantityEligible: no; JH_Trazabilidad - Identificador del objeto: SOURCE-PLAN-PPU-A-PLAN; Estado de la información: Referencia de plano; Aplicabilidad a mediciones: No medible: referencia gráfica conservada; no contar como equipo.; Objeto original: PPU-A-PLAN; JH_DimensionesDocumentadas - Cota relativa de la superficie de apoyo: 0.1 m; Diámetro exterior ajustado al contorno CAD: 3.6302 m; Error radial máximo del ajuste: 0.001262 m; Número de huellas de apoyo: 4; JH_DetalleGeometrico - sourcePlanRetainedFromObject: PPU-A-PLAN; geometryCopy: Exact vertices and faces from published v4; no added offset.
Plano fuente conservado · Adsorbedor PPU-B / MS1201 | Plano fuente de equipo; capa independiente | Plano del fabricante: implantación de equipos · referencia E7 | 3.7921 | 3.79234 | 0.1 | 286.2 | 286.3 | 24.3365 | 1.12133 | Apoyo relativo +0.100 m; cero absoluto provisional | Plano fuente de equipo; capa independiente | sourcePlanReference | {"name":"No especificado","source":"Los contornos revisados no especifican el material del equipo.","status":"unknown"} | {"documented":[{"label":"Diámetro exterior ajustado al contorno CAD","value":3.630221,"unit":"m","source":"EQ-IMPLANTACION-20260430 · polilínea 9C27E","status":"derivado"},{"label":"Error radial máximo del ajuste","value":0.001255,"unit":"m","source":"EQ-IMPLANTACION-20260430 · polilínea 9C27E","status":"derivado"},{"label":"Número de huellas de apoyo","value":4,"unit":"ud","source":"EQ-IMPLANTACION-20260430 · 9C27F,9C280,9C281,9C282","status":"derivado"},{"label":"Cota relativa de la superficie de apoyo","value":0.1,"unit":"m","source":"LHD2609-JG00100-20260904 · sección 3 / 3-3 · 28D00, 28D41","status":"documentado"}],"geometry":[{"label":"Extensión de la malla en X","value":3.7921010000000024,"unit":"m","source":"Geometría releída del IFC; datum absoluto de proceso provisional","status":"derivado"},{"label":"Extensión de la malla en Y","value":3.7923410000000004,"unit":"m","source":"Geometría releída del IFC; datum absoluto de proceso provisional","status":"derivado"},{"label":"Extensión de la malla en Z","value":0.10000000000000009,"unit":"m","source":"Geometría releída del IFC; datum absoluto de proceso provisional","status":"derivado"},{"label":"Cota inferior de visualización","value":286.2,"unit":"m","source":"Geometría releída del IFC; datum absoluto de proceso provisional","status":"derivado"},{"label":"Cota superior de visualización","value":286.3,"unit":"m","source":"Geometría releída del IFC; datum absoluto de proceso provisional","status":"derivado"}],"notes":["Geometría exterior de referencia; los volúmenes no representan cantidades de material, compra o fabricación."]} | {"documentId":"EQ-IMPLANTACION-20260430","title":"Plano del fabricante: implantación de equipos · referencia E7","sheet":"Espacio modelo; referencia E7 en el nombre del archivo","date":"2026-04-30"} | {"Estado de la planta":"Derivado del CAD y del giro de implantación","Nivel relativo del apoyo (m)":0.1,"Estado del nivel relativo":"Documentado en el plano de cimentaciones","Cero absoluto de visualización (m)":286.1,"Estado del cero absoluto":"Provisional","Cota del apoyo de visualización (m)":286.20000000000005,"Desplazamiento aplicado a la malla (m)":0.10000000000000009,"Criterio":"Nivel de apoyo relativo documentado. Se adopta el cero de proceso a 286,10 m solo para visualización; la equivalencia absoluta no está confirmada. No se añade un espesor de montaje sin cota del fabricante."} | ["Copia exacta del plano de referencia previo; no constituye un segundo equipo ni una segunda cimentación.","Espesor de 0,10 m exclusivamente gráfico; mantener esta capa independiente del volumen de referencia."] | {"sourcePlanRetainedFromObject":"PPU-B-PLAN","sourcePlanRetainedFromGuid":"2wDdytY8bU5e9Eo4CEDi5M","geometryCopy":"Exact vertices and faces from published v4; no added offset."} | {"boundingBoxM":{"min":[54.835505,53.863074,1.2],"max":[58.627606,57.655415,1.3]},"extentsM":[3.792101,3.792341,0.1],"meshSurfaceM2":24.336539,"meshVolumeM3":1.121333,"closedSolid":true,"basis":"Geometría de coordinación. Los volúmenes de referencia y subcomponentes no son cantidades de material ni componentes de fabricación certificados."} | {"documentId":"LHD2609-JG00100-20260904","title":"Cimentaciones y pedestales de equipos · revisión recibida 04/09/2026","date":"2026-09-04","sheet":"3 / 3-3","sourceHandles":["28D00","28D41"]} | references | {"id":"references","name":"Referencias documentales"} | {"profileId":"survey_reference","name":"Referencia documental · ámbar","appearanceStatus":"referencia","appearanceBasis":"Interpretación visual del material documental; el acabado, tono y parámetros PBR no son una especificación contractual."} |  |  | {"layerId":"references","layerName":"Referencias documentales","role":"Plano fuente de equipo; capa independiente","basis":"Clasificación por función del elemento; no modifica las especificaciones documentales."} | {"profileId":"survey_reference","name":"Referencia documental · ámbar","status":"referencia","basis":"Interpretación visual del material documental; el acabado, tono y parámetros PBR no son una especificación contractual.","physicalMaterialUnchanged":true} |  |  | Referencias documentales | Referencia documental · ámbar | referencia | SOURCE-PLAN-PPU-B-PLAN | ["Copia exacta del plano de referencia previo; no constituye un segundo equipo ni una segunda cimentación.","Espesor de 0,10 m exclusivamente gráfico; mantener esta capa independiente del volumen de referencia."] | Geometría de coordinación. Los volúmenes de referencia y subcomponentes no son cantidades de material ni componentes de fabricación certificados. | Los contornos revisados no especifican el material del equipo. |  | no | survey_reference | [0.784314,0.584314,0.282353] | 1 | 0 | Interpretación visual del material documental; el acabado, tono y parámetros PBR no son una especificación contractual. | La apariencia no certifica el material físico ni el acabado de fabricación. | BIM · Referencias documentales | JH_InformacionBIM - foundationIds: []; heightStatus: not_applicable; isReferenceOnly: yes; sourceReferenceOf: PPU-B-PLAN; quantityEligible: no; JH_Trazabilidad - Identificador del objeto: SOURCE-PLAN-PPU-B-PLAN; Estado de la información: Referencia de plano; Aplicabilidad a mediciones: No medible: referencia gráfica conservada; no contar como equipo.; Objeto original: PPU-B-PLAN; JH_DimensionesDocumentadas - Cota relativa de la superficie de apoyo: 0.1 m; Diámetro exterior ajustado al contorno CAD: 3.63022 m; Error radial máximo del ajuste: 0.001255 m; Número de huellas de apoyo: 4; JH_DetalleGeometrico - sourcePlanRetainedFromObject: PPU-B-PLAN; geometryCopy: Exact vertices and faces from published v4; no added offset.
Plano fuente conservado · Grupo de bombas de circulación y dosificación | Plano fuente de equipo; capa independiente | Plano del fabricante: cargas de equipos | 6.07843 | 2.14783 | 0.1 | 286.3 | 286.4 | 17.525 | 0.80325 | Apoyo relativo +0.200 m; cero absoluto provisional | Plano fuente de equipo; capa independiente | sourcePlanReference | {"name":"No especificado","source":"Sin especificación de material en la documentación revisada","status":"unknown"} | {"documented":[{"label":"Dimensión X local del grupo","value":5.95,"unit":"m","source":"EQ-CARGAS-20260825 · contorno 260E","status":"derivado"},{"label":"Dimensión Y local del grupo","value":1.35,"unit":"m","source":"EQ-CARGAS-20260825 · contorno 260E","status":"derivado"},{"label":"Límite superior de altura, no altura física confirmada","value":2,"unit":"m","source":"EQ-CARGAS-20260825 · indicación ≤ 2 m · handle 260A","status":"documentado"},{"label":"Cota relativa de la superficie de apoyo","value":0.2,"unit":"m","source":"LHD2609-JG00100-20260904 · sección 10–12 / 10-10 · 2484F, 24886","status":"documentado"}],"geometry":[{"label":"Extensión de la malla en X","value":6.078426,"unit":"m","source":"Geometría releída del IFC; datum absoluto de proceso provisional","status":"derivado"},{"label":"Extensión de la malla en Y","value":2.147832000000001,"unit":"m","source":"Geometría releída del IFC; datum absoluto de proceso provisional","status":"derivado"},{"label":"Extensión de la malla en Z","value":0.09999999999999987,"unit":"m","source":"Geometría releída del IFC; datum absoluto de proceso provisional","status":"derivado"},{"label":"Cota inferior de visualización","value":286.3,"unit":"m","source":"Geometría releída del IFC; datum absoluto de proceso provisional","status":"derivado"},{"label":"Cota superior de visualización","value":286.4,"unit":"m","source":"Geometría releída del IFC; datum absoluto de proceso provisional","status":"derivado"}],"notes":["Las extensiones de la malla se miden en los ejes del proyecto tras el giro de implantación; no sustituyen las dimensiones locales del fabricante.","La envolvente, su volumen y los espesores de visualización no son volúmenes de material ni cantidades de compra, construcción o fabricación.","Las dimensiones documentadas distinguen cotas explícitas y medidas extraídas de contornos CAD; las dimensiones geométricas describen únicamente la malla publicada."]} | {"documentId":"EQ-CARGAS-20260825","title":"Plano del fabricante: cargas de equipos","sheet":"Espacio modelo; número de plano no identificado","date":"2026-08-25"} | {"Estado de la planta":"Derivado del CAD y del giro de implantación","Nivel relativo del apoyo (m)":0.2,"Estado del nivel relativo":"Documentado en el plano de cimentaciones","Cero absoluto de visualización (m)":286.1,"Estado del cero absoluto":"Provisional","Cota del apoyo de visualización (m)":286.3,"Desplazamiento aplicado a la malla (m)":0.2000000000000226,"Criterio":"Nivel de apoyo relativo documentado. Se adopta el cero de proceso a 286,10 m solo para visualización; la equivalencia absoluta no está confirmada. No se añade un espesor de montaje sin cota del fabricante."} | ["Copia exacta del plano de referencia previo; no constituye un segundo equipo ni una segunda cimentación.","Espesor de 0,10 m exclusivamente gráfico; mantener esta capa independiente del volumen de referencia."] | {"sourcePlanRetainedFromObject":"PUMPS-DOSING-PLAN","sourcePlanRetainedFromGuid":"3bYFGHJXrP091wOaX29ECq","geometryCopy":"Exact vertices and faces from published v4; no added offset."} | {"boundingBoxM":{"min":[36.575699,55.725405,1.3],"max":[42.654125,57.873237,1.4]},"extentsM":[6.078426,2.147832,0.1],"meshSurfaceM2":17.524998,"meshVolumeM3":0.80325,"closedSolid":true,"basis":"Geometría de coordinación. Los volúmenes de referencia y subcomponentes no son cantidades de material ni componentes de fabricación certificados."} | {"documentId":"LHD2609-JG00100-20260904","title":"Cimentaciones y pedestales de equipos · revisión recibida 04/09/2026","date":"2026-09-04","sheet":"10–12 / 10-10","sourceHandles":["2484F","24886"]} | references | {"id":"references","name":"Referencias documentales"} | {"profileId":"survey_reference","name":"Referencia documental · ámbar","appearanceStatus":"referencia","appearanceBasis":"Interpretación visual del material documental; el acabado, tono y parámetros PBR no son una especificación contractual."} |  |  | {"layerId":"references","layerName":"Referencias documentales","role":"Plano fuente de equipo; capa independiente","basis":"Clasificación por función del elemento; no modifica las especificaciones documentales."} | {"profileId":"survey_reference","name":"Referencia documental · ámbar","status":"referencia","basis":"Interpretación visual del material documental; el acabado, tono y parámetros PBR no son una especificación contractual.","physicalMaterialUnchanged":true} |  |  | Referencias documentales | Referencia documental · ámbar | referencia | SOURCE-PLAN-PUMPS-DOSING-PLAN | ["Copia exacta del plano de referencia previo; no constituye un segundo equipo ni una segunda cimentación.","Espesor de 0,10 m exclusivamente gráfico; mantener esta capa independiente del volumen de referencia."] | Geometría de coordinación. Los volúmenes de referencia y subcomponentes no son cantidades de material ni componentes de fabricación certificados. | Sin especificación de material en la documentación revisada |  | no | survey_reference | [0.784314,0.584314,0.282353] | 1 | 0 | Interpretación visual del material documental; el acabado, tono y parámetros PBR no son una especificación contractual. | La apariencia no certifica el material físico ni el acabado de fabricación. | BIM · Referencias documentales | JH_InformacionBIM - foundationIds: []; heightStatus: not_applicable; isReferenceOnly: yes; sourceReferenceOf: PUMPS-DOSING-PLAN; quantityEligible: no; JH_Trazabilidad - Identificador del objeto: SOURCE-PLAN-PUMPS-DOSING-PLAN; Estado de la información: Referencia de plano; Aplicabilidad a mediciones: No medible: referencia gráfica conservada; no contar como equipo.; Objeto original: PUMPS-DOSING-PLAN; JH_DimensionesDocumentadas - Cota relativa de la superficie de apoyo: 0.2 m; Dimensión X local del grupo: 5.95 m; Dimensión Y local del grupo: 1.35 m; Límite superior de altura, no altura física confirmada: 2 m; JH_DetalleGeometrico - sourcePlanRetainedFromObject: PUMPS-DOSING-PLAN; geometryCopy: Exact vertices and faces from published v4; no added offset.
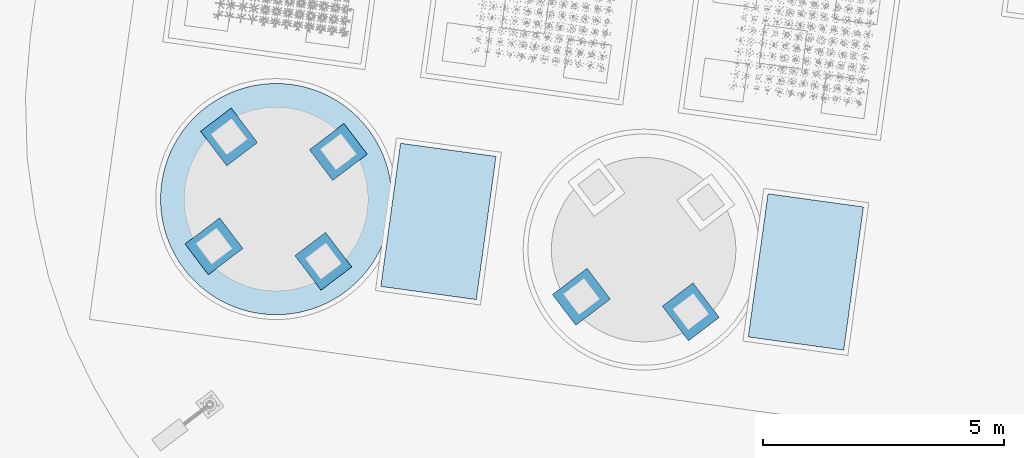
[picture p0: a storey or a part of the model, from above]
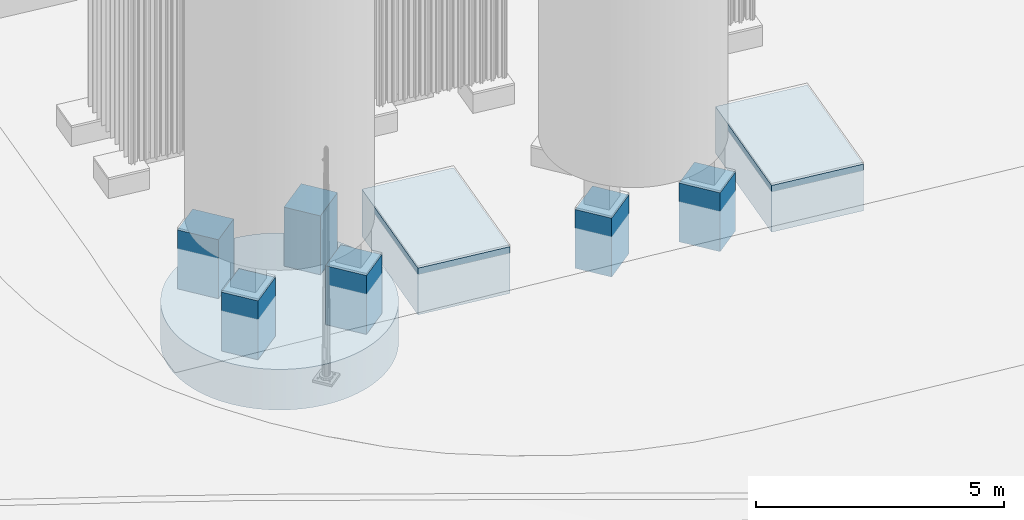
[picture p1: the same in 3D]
Properties of the parts of a building model (IFC4), part 11 of 134

# IfcBuildingElementProxy (140)
Name | Description | Document | Extensión de la malla en X (m) = ExtensionX (m) | Extensión de la malla en Y (m) = ExtensionY (m) | Extensión de la malla en Z (m) = ExtensionZ (m) | Cota inferior de visualización (m) | Cota superior de visualización (m) | SuperficieDeLaMalla (m2) | VolumenGeometrico (m3) | level | category = Categoria = Funcion | representationKind | material | dimensions | JH_InformacionBIM, source = DocumentoFuente | positioning = PosicionYEstado | issues | detailGeometry | geometryMetrics | installationSource | layerId = IdentificadorCapa | visualLayer | materialAppearance | componentSeparation | visualizationIdentity | classification | appearance | Disciplina | Material | Capa BIM = NombreCapa | Acabado de visualización = Acabado | Estado del acabado = Estado | Identificador | JH_Trazabilidad, IncidenciasPendientes | UsoDeLasMagnitudes | JH_EvidenciaDeMaterial, source | JH_DetalleGeometrico, source | VisibilidadInicial | Perfil | ColorRGB | Rugosidad | Metallicidad | Referencia | Nota | Group | parentEquipmentId = Identificador del equipo padre | parentEquipmentName = Equipo padre | parentEquipmentIfcClass | parentEquipmentDimensions | parentEquipmentPositioning | parentEquipmentIssues | parentEquipmentDetail | componentRole = Rol del componente | assemblyBBox | assemblyGeometryMetrics | manufacturerDetailsPending | component | assembly | foundationRelationship | installationSourceScope | Identificador del elemento = sourcePartId | Componente | Capa de visualización | Estado del material | Perfil visual del material | Fuente del componente | Criterio de partición | Criterio de las dimensiones | Relación con cimentaciones | Aplicabilidad de las mediciones | Referencia dimensional del conjunto | sourceHandles | partCount | partsAreBOM | status
Torre de refrigeración WT3001B · Pala de ventilador 4 · contorno CAD | Componente de equipo · cuerpo o accesorio | Plano del fabricante: implantación de equipos · referencia E7 | 0.525639 | 0.627195 | 0.04 | 291.62 | 291.66 | 0.189829 | 0.002482 | Apoyo relativo +2.000 m; cero absoluto provisional | Componente de equipo · cuerpo o accesorio | equipmentComponent | {"name":"No especificado","source":"Sin especificación de material en la documentación revisada","status":"unknown"} | {"documented":[{"label":"Referencia dimensional del conjunto","value":"Plano general y dimensiones globales de WT3001B; no se asignan esas dimensiones globales a este componente.","unit":"","source":"EQ-IMPLANTACION-20260430 · LHD2609-GD01000 · espacio modelo","status":"referencia_del_conjunto"}],"geometry":[{"label":"Extensión de la malla en X","value":0.5256390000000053,"unit":"m","source":"Geometría releída del IFC; datum absoluto de proceso provisional","status":"derivado"},{"label":"Extensión de la malla en Y","value":0.6271949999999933,"unit":"m","source":"Geometría releída del IFC; datum absoluto de proceso provisional","status":"derivado"},{"label":"Extensión de la malla en Z","value":0.040000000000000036,"unit":"m","source":"Geometría releída del IFC; datum absoluto de proceso provisional","status":"derivado"},{"label":"Cota inferior de visualización","value":291.62,"unit":"m","source":"Geometría releída del IFC; datum absoluto de proceso provisional","status":"derivado"},{"label":"Cota superior de visualización","value":291.66,"unit":"m","source":"Geometría releída del IFC; datum absoluto de proceso provisional","status":"derivado"}],"notes":["Las dimensiones del equipo completo se conservan en parentEquipmentDimensions.","Las extensiones en X/Y son de los ejes del modelo y no sustituyen cotas locales de fabricación.","No se infieren espesores de chapa, tolerancias ni dimensiones de piezas a partir de la partición."]} | {"documentId":"EQ-IMPLANTACION-20260430","title":"Plano del fabricante: implantación de equipos","sheet":"LHD2609-GD01000 · espacio modelo","date":"2026-04-30","componentSourceHandles":["70970"]} | {"horizontalStatus":"derivado_del_conjunto","verticalStatus":"derivado_del_conjunto","coordinateSystem":"model_local_m","parentEquipmentId":"WT3001B","transformApplied":false,"note":"Coordenadas copiadas exactamente del equipo coordinado; no se ha movido, girado, elevado ni reescalado este componente.","foundationRelationship":"El apoyo y las cotas de instalación se documentan para el conjunto padre. Esta submalla no acredita un anclaje directo.","meshMinimumAbsoluteElevationM":291.62,"assemblyPlacementField":"parentEquipmentPositioning"} | ["Componente separado de una reconstrucción documental del conjunto. Las alturas y detalles parciales conservan las limitaciones del fabricante registradas en parentEquipmentIssues.","Esta representación exterior no crea una chapa hueca ni añade componentes internos no documentados.","La pertenencia al conjunto no demuestra apoyo o anclaje directo a la cimentación."] | {"source":{"documentId":"EQ-IMPLANTACION-20260430","title":"Plano del fabricante: implantación de equipos","sheet":"LHD2609-GD01000 · espacio modelo","date":"2026-04-30","componentSourceHandles":["70970"]},"sourcePartId":"WT3001B--blade-04","sourceHandles":["70970"],"partCount":1,"partsAreBOM":false,"status":"Submalla exacta; interpretación funcional y cotas parciales provisionales."} | {"boundingBoxM":{"min":[39.523869,47.90306,6.62],"max":[40.049508,48.530255,6.66]},"extentsM":[0.525639,0.627195,0.04],"meshSurfaceM2":0.189829,"meshVolumeM3":0.002482,"closedSolid":true,"basis":"Geometría de coordinación. Los volúmenes de referencia y subcomponentes no son cantidades de material ni componentes de fabricación certificados."} | {"documentId":"LHD2609-JG00100-20260904","title":"Cimentaciones y pedestales de equipos · revisión recibida 04/09/2026","date":"2026-09-04","sheet":"9 / 9-9 / 9A-9A","sourceHandles":["2483D","24841","24772"]} | equipment | {"id":"equipment","name":"Equipos"} | {"profileId":"equipment_silver","name":"Intercambiador · metal gris provisional","materialName":"No especificado","physicalMaterialStatus":"unknown","physicalMaterialSource":"Sin especificación de material en la documentación revisada","appearanceStatus":"provisional","appearanceBasis":"Referencia visual de fotografías públicas de Jinhong Gas / fabricante. Apariencia provisional para coordinación; fotografías oficiales pueden orientar el color, pero no acreditan el material, el acabado ni el equipo concreto.","appearanceReferences":["jinhong-official-asu"],"note":"El perfil visual no confirma material, grado ni acabado del componente."} | {"status":"componente_independiente","note":"Objeto independiente seleccionable. Las caras se asignan una sola vez entre todos los componentes del conjunto.","parentEquipmentId":"WT3001B","isAssemblyIdentityCarrier":false} | {"elementId":"WT3001B--blade-04","ifcGuid":"1PWlUDDPjVGwkquDMniUsh","ifcClass":"IfcBuildingElementProxy","buildingId":"process_plant","buildingName":"Planta de proceso","sourceDocumentId":"EQ-IMPLANTACION-20260430","sourceRepresentationKind":"equipmentComponent"} | {"layerId":"equipment","layerName":"Equipos","role":"Componente de equipo · cuerpo o accesorio","basis":"Clasificación por función del elemento; no modifica las especificaciones documentales."} | {"profileId":"equipment_silver","name":"Intercambiador · metal gris provisional","status":"provisional","basis":"Referencia visual de fotografías públicas de Jinhong Gas / fabricante. Apariencia provisional para coordinación; fotografías oficiales pueden orientar el color, pero no acreditan el material, el acabado ni el equipo concreto.","physicalMaterialUnchanged":true} | Equipos | No especificado | Equipos | Intercambiador · metal gris provisional | provisional | WT3001B--blade-04 | ["Componente separado de una reconstrucción documental del conjunto. Las alturas y detalles parciales conservan las limitaciones del fabricante registradas en parentEquipmentIssues.","Esta representación exterior no crea una chapa hueca ni añade componentes internos no documentados.","La pertenencia al conjunto no demuestra apoyo o anclaje directo a la cimentación."] | Geometría de coordinación. Los volúmenes de referencia y subcomponentes no son cantidades de material ni componentes de fabricación certificados. | Sin especificación de material en la documentación revisada | {"documentId":"EQ-IMPLANTACION-20260430","title":"Plano del fabricante: implantación de equipos","sheet":"LHD2609-GD01000 · espacio modelo","date":"2026-04-30","componentSourceHandles":["70970"]} | yes | equipment_silver | [0.68,0.72,0.75] | 0.38 | 0.7 | Referencia visual de fotografías públicas de Jinhong Gas / fabricante. Apariencia provisional para coordinación; fotografías oficiales pueden orientar el color, pero no acreditan el material, el acabado ni el equipo concreto. | La apariencia no certifica el material físico ni el acabado de fabricación. | BIM · Equipos | WT3001B | Torre de refrigeración WT3001B | IfcCoolingTower | {"documented":[{"label":"Dimensión X local del contorno CAD","value":5.85,"unit":"m","source":"EQ-CARGAS-20260825 · contorno CAD · handles 524","status":"derivado"},{"label":"Dimensión Y local del contorno CAD","value":2.14,"unit":"m","source":"EQ-CARGAS-20260825 · contorno CAD · handles 524","status":"derivado"},{"label":"Altura acotada","value":3.7,"unit":"m","source":"EQ-CARGAS-20260825 · handle 2659","status":"documentado"},{"label":"Cota relativa de la superficie de apoyo","value":2.0,"unit":"m","source":"LHD2609-JG00100-20260904 · sección 9 / 9-9 / 9A-9A · 2483D, 24841, 24772","status":"documentado"}],"geometry":[{"label":"Extensión de la malla en X","value":6.086960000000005,"unit":"m","source":"Geometría releída del IFC; datum absoluto de proceso provisional","status":"derivado"},{"label":"Extensión de la malla en Y","value":2.9168499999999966,"unit":"m","source":"Geometría releída del IFC; datum absoluto de proceso provisional","status":"derivado"},{"label":"Extensión de la malla en Z","value":3.6999999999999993,"unit":"m","source":"Geometría releída del IFC; datum absoluto de proceso provisional","status":"derivado"},{"label":"Cota inferior de visualización","value":288.1,"unit":"m","source":"Geometría releída del IFC; datum absoluto de proceso provisional","status":"derivado"},{"label":"Cota superior de visualización","value":291.8,"unit":"m","source":"Geometría releída del IFC; datum absoluto de proceso provisional","status":"derivado"}],"notes":["Las extensiones de la malla se miden en los ejes del proyecto tras el giro de implantación; no sustituyen las dimensiones locales del fabricante.","La envolvente, su volumen y los espesores de visualización no son volúmenes de material ni cantidades de compra, construcción o fabricación.","Las dimensiones documentadas distinguen cotas explícitas y medidas extraídas de contornos CAD; las dimensiones geométricas describen únicamente la malla publicada.","Las extensiones de la malla refinada y las dimensiones documentadas del contorno o bastidor tienen distinto alcance; las cotas parciales del detalle son provisionales."]} | {"Estado de la planta":"Derivado del CAD y del giro de implantación","Nivel relativo del apoyo (m)":2.0,"Estado del nivel relativo":"Documentado en el plano de cimentaciones","Cero absoluto de visualización (m)":286.1,"Estado del cero absoluto":"Provisional","Cota del apoyo de visualización (m)":288.1,"Desplazamiento aplicado a la malla (m)":2.0000000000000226,"Criterio":"Nivel de apoyo relativo documentado. Se adopta el cero de proceso a 286,10 m solo para visualización; la equivalencia absoluta no está confirmada. No se añade un espesor de montaje sin cota del fabricante."} | ["La masa de 5 750 kg por unidad es el reparto uniforme de 23 000 kg del conjunto; confirmar el reparto real de cargas. Barandillas y sombreretes no se detallan.","El detalle de abril presenta una célula de 5,85 × 2,20 m; el contorno de agosto es de 5,85 × 2,14 m. Se usa el contorno de agosto. El ventilador se traslada al nuevo centro sin alterar su diámetro ni sus palas.","Las cotas intermedias 3,20 / 3,40 / 3,52 / 3,56 m no aparecen acotadas en el fabricante.","Espesor de palas de 0,04 m y altura del aro de 0,30 m: hipótesis de visualización.","La sección y altura reales de la estructura y de los paneles permanecen sin confirmar.","Los 25 pilares DZ9 terminan en +2,000; los cinco muros transversales terminan en +1,000. La instalación se asocia a los pilares superiores. El plano conserva -2,200 frente al fondo -2,000 de la sección.","El cero absoluto de la revisión no está definido; 286,10 m sigue siendo una hipótesis de coordinación.","Se alinea el punto inferior del conjunto del equipo, incluidos los pies ya representados, con la superficie de apoyo terminada; no se añade un espesor de calzos, placa o grout del fabricante no documentado."] | {"revision":"Detalle en planta de 2026-04-30 coordinado de forma preliminar con envolventes y alturas de 2026-08-25","status":"provisional","verticalRule":"Altura total documentada: 3,70 m. Distribución conceptual: cuerpo 0–3,20 m; plataforma superior 3,20–3,40 m; aro del ventilador 3,40–3,70 m; palas 3,52–3,56 m.","partCount":12,"source":{"documentId":"EQ-IMPLANTACION-20260430","title":"Plano del fabricante: implantación de equipos","sheet":"LHD2609-GD01000 · espacio modelo","date":"2026-04-30"},"heightSource":{"documentId":"EQ-CARGAS-20260825","title":"Plano del fabricante: cargas de equipos","sheet":"Espacio modelo","date":"2026-08-25"},"unconfirmedDimensions":["Las cotas intermedias 3,20 / 3,40 / 3,52 / 3,56 m no aparecen acotadas en el fabricante.","Espesor de palas de 0,04 m y altura del aro de 0,30 m: hipótesis de visualización.","La sección y altura reales de la estructura y de los paneles permanecen sin confirmar."],"quantityUse":"Magnitudes de la geometría representada; no son cantidades de material, obra, compra, capacidad útil ni fabricación. En geometrías compuestas se suman superficies y volúmenes de partes y pueden existir solapes no depurados.","partsAreBOM":false} | equipment_component | {"min":[36.44488,46.344292,3.1],"max":[42.53184,49.261142,6.8]} | {"boundingBoxM":{"min":[36.44488,46.344292,3.1],"max":[42.53184,49.261142,6.8]},"extentsM":[6.086960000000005,2.9168499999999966,3.6999999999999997],"meshSurfaceM2":106.9519119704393,"meshVolumeM3":42.21444876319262,"closedSolid":true,"windingConsistent":true,"basis":"Submalla exacta de los triángulos del modelo IFC coordinado; separación de componentes sin transformación ni retesselación."} | ["Las cotas intermedias 3,20 / 3,40 / 3,52 / 3,56 m no aparecen acotadas en el fabricante.","Espesor de palas de 0,04 m y altura del aro de 0,30 m: hipótesis de visualización.","La sección y altura reales de la estructura y de los paneles permanecen sin confirmar.","La separación gráfica no aporta cotas de fabricación ni identifica piezas internas no documentadas.","Los materiales y acabados permanecen provisionales; las fotografías públicas solo orientan la apariencia."] | {"id":"WT3001B--blade-04","sourcePartId":"WT3001B--blade-04","name":"Pala de ventilador 4 · contorno CAD","role":"equipment_component","classificationStatus":"provisional","classificationBasis":"Rol del subvolumen gráfico según el activo de detalle; identidad de fabricación no confirmada.","parentEquipmentId":"WT3001B","parentEquipmentGuid":"3QfAgBB2zPsvSc6AB8$nne","isAssemblyIdentityCarrier":false,"sourceFaceRange":[2392,2412],"sourceCurrentFaceIndices":[2392,2393,2394,2395,2396,2397,2398,2399,2400,2401,2402,2403,2404,2405,2406,2407,2408,2409,2410,2411],"sourceMeshSha256":"7b60c904c9d84d22fded9be34af09a09a9c198ec8e75e61902634d5e4064c761","sourceVertexIndices":[1204,1205,1206,1207,1208,1209,1210,1211,1212,1213,1214,1215],"separationMethod":"Partición exacta de triángulos existentes; coordenadas y orientación de caras conservadas.","quantityUse":"Magnitudes geométricas del subvolumen; no son cantidades netas de material, fabricación, suministro o capacidad."} | {"id":"WT3001B","name":"Torre de refrigeración WT3001B","relationship":"decomposed_component","parentShapeMeaning":"La forma del objeto que conserva el ID del equipo es únicamente su componente principal; el conjunto completo requiere sus hijos."} | {"kind":"through_parent","parentEquipmentId":"WT3001B","directAnchorageVerified":false,"note":"La relación del conjunto con cimentaciones se conserva en el objeto que mantiene el ID del equipo; no se atribuye fijación directa a cada subcomponente."} | Documento de implantación y apoyo del conjunto padre; no acredita fijación individual de este componente. | WT3001B--blade-04 | Pala de ventilador 4 · contorno CAD | Equipos | unknown | equipment_silver | {"documentId":"EQ-IMPLANTACION-20260430","title":"Plano del fabricante: implantación de equipos","sheet":"LHD2609-GD01000 · espacio modelo","date":"2026-04-30","componentSourceHandles":["70970"]} | Submalla de triángulos existentes; no hay nueva posición ni nuevas caras. | Cotas globales del conjunto conservadas aparte; las dimensiones de esta ficha son de la submalla. | Coordinación del conjunto padre; anclaje directo individual no acreditado. | Superficie y volumen geométricos brutos; no constituyen cantidades netas de obra, material o fabricación. | Plano general y dimensiones globales de WT3001B; no se asignan esas dimensiones globales a este componente. | ["70970"] | 1 | no | Submalla exacta; interpretación funcional y cotas parciales provisionales.
Torre de refrigeración WT3001B · Pala de ventilador 5 · contorno CAD | Componente de equipo · cuerpo o accesorio | Plano del fabricante: implantación de equipos · referencia E7 | 0.748145 | 0.186061 | 0.04 | 291.62 | 291.66 | 0.18983 | 0.002482 | Apoyo relativo +2.000 m; cero absoluto provisional | Componente de equipo · cuerpo o accesorio | equipmentComponent | {"name":"No especificado","source":"Sin especificación de material en la documentación revisada","status":"unknown"} | {"documented":[{"label":"Referencia dimensional del conjunto","value":"Plano general y dimensiones globales de WT3001B; no se asignan esas dimensiones globales a este componente.","unit":"","source":"EQ-IMPLANTACION-20260430 · LHD2609-GD01000 · espacio modelo","status":"referencia_del_conjunto"}],"geometry":[{"label":"Extensión de la malla en X","value":0.748145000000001,"unit":"m","source":"Geometría releída del IFC; datum absoluto de proceso provisional","status":"derivado"},{"label":"Extensión de la malla en Y","value":0.18606099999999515,"unit":"m","source":"Geometría releída del IFC; datum absoluto de proceso provisional","status":"derivado"},{"label":"Extensión de la malla en Z","value":0.040000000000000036,"unit":"m","source":"Geometría releída del IFC; datum absoluto de proceso provisional","status":"derivado"},{"label":"Cota inferior de visualización","value":291.62,"unit":"m","source":"Geometría releída del IFC; datum absoluto de proceso provisional","status":"derivado"},{"label":"Cota superior de visualización","value":291.66,"unit":"m","source":"Geometría releída del IFC; datum absoluto de proceso provisional","status":"derivado"}],"notes":["Las dimensiones del equipo completo se conservan en parentEquipmentDimensions.","Las extensiones en X/Y son de los ejes del modelo y no sustituyen cotas locales de fabricación.","No se infieren espesores de chapa, tolerancias ni dimensiones de piezas a partir de la partición."]} | {"documentId":"EQ-IMPLANTACION-20260430","title":"Plano del fabricante: implantación de equipos","sheet":"LHD2609-GD01000 · espacio modelo","date":"2026-04-30","componentSourceHandles":["7098A"]} | {"horizontalStatus":"derivado_del_conjunto","verticalStatus":"derivado_del_conjunto","coordinateSystem":"model_local_m","parentEquipmentId":"WT3001B","transformApplied":false,"note":"Coordenadas copiadas exactamente del equipo coordinado; no se ha movido, girado, elevado ni reescalado este componente.","foundationRelationship":"El apoyo y las cotas de instalación se documentan para el conjunto padre. Esta submalla no acredita un anclaje directo.","meshMinimumAbsoluteElevationM":291.62,"assemblyPlacementField":"parentEquipmentPositioning"} | ["Componente separado de una reconstrucción documental del conjunto. Las alturas y detalles parciales conservan las limitaciones del fabricante registradas en parentEquipmentIssues.","Esta representación exterior no crea una chapa hueca ni añade componentes internos no documentados.","La pertenencia al conjunto no demuestra apoyo o anclaje directo a la cimentación."] | {"source":{"documentId":"EQ-IMPLANTACION-20260430","title":"Plano del fabricante: implantación de equipos","sheet":"LHD2609-GD01000 · espacio modelo","date":"2026-04-30","componentSourceHandles":["7098A"]},"sourcePartId":"WT3001B--blade-05","sourceHandles":["7098A"],"partCount":1,"partsAreBOM":false,"status":"Submalla exacta; interpretación funcional y cotas parciales provisionales."} | {"boundingBoxM":{"min":[39.626596,47.662151,6.62],"max":[40.374741,47.848212,6.66]},"extentsM":[0.748145,0.186061,0.04],"meshSurfaceM2":0.18983,"meshVolumeM3":0.002482,"closedSolid":true,"basis":"Geometría de coordinación. Los volúmenes de referencia y subcomponentes no son cantidades de material ni componentes de fabricación certificados."} | {"documentId":"LHD2609-JG00100-20260904","title":"Cimentaciones y pedestales de equipos · revisión recibida 04/09/2026","date":"2026-09-04","sheet":"9 / 9-9 / 9A-9A","sourceHandles":["2483D","24841","24772"]} | equipment | {"id":"equipment","name":"Equipos"} | {"profileId":"equipment_silver","name":"Intercambiador · metal gris provisional","materialName":"No especificado","physicalMaterialStatus":"unknown","physicalMaterialSource":"Sin especificación de material en la documentación revisada","appearanceStatus":"provisional","appearanceBasis":"Referencia visual de fotografías públicas de Jinhong Gas / fabricante. Apariencia provisional para coordinación; fotografías oficiales pueden orientar el color, pero no acreditan el material, el acabado ni el equipo concreto.","appearanceReferences":["jinhong-official-asu"],"note":"El perfil visual no confirma material, grado ni acabado del componente."} | {"status":"componente_independiente","note":"Objeto independiente seleccionable. Las caras se asignan una sola vez entre todos los componentes del conjunto.","parentEquipmentId":"WT3001B","isAssemblyIdentityCarrier":false} | {"elementId":"WT3001B--blade-05","ifcGuid":"01J_TT6sbR8OXfUQkjbdl8","ifcClass":"IfcBuildingElementProxy","buildingId":"process_plant","buildingName":"Planta de proceso","sourceDocumentId":"EQ-IMPLANTACION-20260430","sourceRepresentationKind":"equipmentComponent"} | {"layerId":"equipment","layerName":"Equipos","role":"Componente de equipo · cuerpo o accesorio","basis":"Clasificación por función del elemento; no modifica las especificaciones documentales."} | {"profileId":"equipment_silver","name":"Intercambiador · metal gris provisional","status":"provisional","basis":"Referencia visual de fotografías públicas de Jinhong Gas / fabricante. Apariencia provisional para coordinación; fotografías oficiales pueden orientar el color, pero no acreditan el material, el acabado ni el equipo concreto.","physicalMaterialUnchanged":true} | Equipos | No especificado | Equipos | Intercambiador · metal gris provisional | provisional | WT3001B--blade-05 | ["Componente separado de una reconstrucción documental del conjunto. Las alturas y detalles parciales conservan las limitaciones del fabricante registradas en parentEquipmentIssues.","Esta representación exterior no crea una chapa hueca ni añade componentes internos no documentados.","La pertenencia al conjunto no demuestra apoyo o anclaje directo a la cimentación."] | Geometría de coordinación. Los volúmenes de referencia y subcomponentes no son cantidades de material ni componentes de fabricación certificados. | Sin especificación de material en la documentación revisada | {"documentId":"EQ-IMPLANTACION-20260430","title":"Plano del fabricante: implantación de equipos","sheet":"LHD2609-GD01000 · espacio modelo","date":"2026-04-30","componentSourceHandles":["7098A"]} | yes | equipment_silver | [0.68,0.72,0.75] | 0.38 | 0.7 | Referencia visual de fotografías públicas de Jinhong Gas / fabricante. Apariencia provisional para coordinación; fotografías oficiales pueden orientar el color, pero no acreditan el material, el acabado ni el equipo concreto. | La apariencia no certifica el material físico ni el acabado de fabricación. | BIM · Equipos | WT3001B | Torre de refrigeración WT3001B | IfcCoolingTower | {"documented":[{"label":"Dimensión X local del contorno CAD","value":5.85,"unit":"m","source":"EQ-CARGAS-20260825 · contorno CAD · handles 524","status":"derivado"},{"label":"Dimensión Y local del contorno CAD","value":2.14,"unit":"m","source":"EQ-CARGAS-20260825 · contorno CAD · handles 524","status":"derivado"},{"label":"Altura acotada","value":3.7,"unit":"m","source":"EQ-CARGAS-20260825 · handle 2659","status":"documentado"},{"label":"Cota relativa de la superficie de apoyo","value":2.0,"unit":"m","source":"LHD2609-JG00100-20260904 · sección 9 / 9-9 / 9A-9A · 2483D, 24841, 24772","status":"documentado"}],"geometry":[{"label":"Extensión de la malla en X","value":6.086960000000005,"unit":"m","source":"Geometría releída del IFC; datum absoluto de proceso provisional","status":"derivado"},{"label":"Extensión de la malla en Y","value":2.9168499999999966,"unit":"m","source":"Geometría releída del IFC; datum absoluto de proceso provisional","status":"derivado"},{"label":"Extensión de la malla en Z","value":3.6999999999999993,"unit":"m","source":"Geometría releída del IFC; datum absoluto de proceso provisional","status":"derivado"},{"label":"Cota inferior de visualización","value":288.1,"unit":"m","source":"Geometría releída del IFC; datum absoluto de proceso provisional","status":"derivado"},{"label":"Cota superior de visualización","value":291.8,"unit":"m","source":"Geometría releída del IFC; datum absoluto de proceso provisional","status":"derivado"}],"notes":["Las extensiones de la malla se miden en los ejes del proyecto tras el giro de implantación; no sustituyen las dimensiones locales del fabricante.","La envolvente, su volumen y los espesores de visualización no son volúmenes de material ni cantidades de compra, construcción o fabricación.","Las dimensiones documentadas distinguen cotas explícitas y medidas extraídas de contornos CAD; las dimensiones geométricas describen únicamente la malla publicada.","Las extensiones de la malla refinada y las dimensiones documentadas del contorno o bastidor tienen distinto alcance; las cotas parciales del detalle son provisionales."]} | {"Estado de la planta":"Derivado del CAD y del giro de implantación","Nivel relativo del apoyo (m)":2.0,"Estado del nivel relativo":"Documentado en el plano de cimentaciones","Cero absoluto de visualización (m)":286.1,"Estado del cero absoluto":"Provisional","Cota del apoyo de visualización (m)":288.1,"Desplazamiento aplicado a la malla (m)":2.0000000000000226,"Criterio":"Nivel de apoyo relativo documentado. Se adopta el cero de proceso a 286,10 m solo para visualización; la equivalencia absoluta no está confirmada. No se añade un espesor de montaje sin cota del fabricante."} | ["La masa de 5 750 kg por unidad es el reparto uniforme de 23 000 kg del conjunto; confirmar el reparto real de cargas. Barandillas y sombreretes no se detallan.","El detalle de abril presenta una célula de 5,85 × 2,20 m; el contorno de agosto es de 5,85 × 2,14 m. Se usa el contorno de agosto. El ventilador se traslada al nuevo centro sin alterar su diámetro ni sus palas.","Las cotas intermedias 3,20 / 3,40 / 3,52 / 3,56 m no aparecen acotadas en el fabricante.","Espesor de palas de 0,04 m y altura del aro de 0,30 m: hipótesis de visualización.","La sección y altura reales de la estructura y de los paneles permanecen sin confirmar.","Los 25 pilares DZ9 terminan en +2,000; los cinco muros transversales terminan en +1,000. La instalación se asocia a los pilares superiores. El plano conserva -2,200 frente al fondo -2,000 de la sección.","El cero absoluto de la revisión no está definido; 286,10 m sigue siendo una hipótesis de coordinación.","Se alinea el punto inferior del conjunto del equipo, incluidos los pies ya representados, con la superficie de apoyo terminada; no se añade un espesor de calzos, placa o grout del fabricante no documentado."] | {"revision":"Detalle en planta de 2026-04-30 coordinado de forma preliminar con envolventes y alturas de 2026-08-25","status":"provisional","verticalRule":"Altura total documentada: 3,70 m. Distribución conceptual: cuerpo 0–3,20 m; plataforma superior 3,20–3,40 m; aro del ventilador 3,40–3,70 m; palas 3,52–3,56 m.","partCount":12,"source":{"documentId":"EQ-IMPLANTACION-20260430","title":"Plano del fabricante: implantación de equipos","sheet":"LHD2609-GD01000 · espacio modelo","date":"2026-04-30"},"heightSource":{"documentId":"EQ-CARGAS-20260825","title":"Plano del fabricante: cargas de equipos","sheet":"Espacio modelo","date":"2026-08-25"},"unconfirmedDimensions":["Las cotas intermedias 3,20 / 3,40 / 3,52 / 3,56 m no aparecen acotadas en el fabricante.","Espesor de palas de 0,04 m y altura del aro de 0,30 m: hipótesis de visualización.","La sección y altura reales de la estructura y de los paneles permanecen sin confirmar."],"quantityUse":"Magnitudes de la geometría representada; no son cantidades de material, obra, compra, capacidad útil ni fabricación. En geometrías compuestas se suman superficies y volúmenes de partes y pueden existir solapes no depurados.","partsAreBOM":false} | equipment_component | {"min":[36.44488,46.344292,3.1],"max":[42.53184,49.261142,6.8]} | {"boundingBoxM":{"min":[36.44488,46.344292,3.1],"max":[42.53184,49.261142,6.8]},"extentsM":[6.086960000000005,2.9168499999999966,3.6999999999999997],"meshSurfaceM2":106.9519119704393,"meshVolumeM3":42.21444876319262,"closedSolid":true,"windingConsistent":true,"basis":"Submalla exacta de los triángulos del modelo IFC coordinado; separación de componentes sin transformación ni retesselación."} | ["Las cotas intermedias 3,20 / 3,40 / 3,52 / 3,56 m no aparecen acotadas en el fabricante.","Espesor de palas de 0,04 m y altura del aro de 0,30 m: hipótesis de visualización.","La sección y altura reales de la estructura y de los paneles permanecen sin confirmar.","La separación gráfica no aporta cotas de fabricación ni identifica piezas internas no documentadas.","Los materiales y acabados permanecen provisionales; las fotografías públicas solo orientan la apariencia."] | {"id":"WT3001B--blade-05","sourcePartId":"WT3001B--blade-05","name":"Pala de ventilador 5 · contorno CAD","role":"equipment_component","classificationStatus":"provisional","classificationBasis":"Rol del subvolumen gráfico según el activo de detalle; identidad de fabricación no confirmada.","parentEquipmentId":"WT3001B","parentEquipmentGuid":"3QfAgBB2zPsvSc6AB8$nne","isAssemblyIdentityCarrier":false,"sourceFaceRange":[2412,2432],"sourceCurrentFaceIndices":[2412,2413,2414,2415,2416,2417,2418,2419,2420,2421,2422,2423,2424,2425,2426,2427,2428,2429,2430,2431],"sourceMeshSha256":"7b60c904c9d84d22fded9be34af09a09a9c198ec8e75e61902634d5e4064c761","sourceVertexIndices":[1216,1217,1218,1219,1220,1221,1222,1223,1224,1225,1226,1227],"separationMethod":"Partición exacta de triángulos existentes; coordenadas y orientación de caras conservadas.","quantityUse":"Magnitudes geométricas del subvolumen; no son cantidades netas de material, fabricación, suministro o capacidad."} | {"id":"WT3001B","name":"Torre de refrigeración WT3001B","relationship":"decomposed_component","parentShapeMeaning":"La forma del objeto que conserva el ID del equipo es únicamente su componente principal; el conjunto completo requiere sus hijos."} | {"kind":"through_parent","parentEquipmentId":"WT3001B","directAnchorageVerified":false,"note":"La relación del conjunto con cimentaciones se conserva en el objeto que mantiene el ID del equipo; no se atribuye fijación directa a cada subcomponente."} | Documento de implantación y apoyo del conjunto padre; no acredita fijación individual de este componente. | WT3001B--blade-05 | Pala de ventilador 5 · contorno CAD | Equipos | unknown | equipment_silver | {"documentId":"EQ-IMPLANTACION-20260430","title":"Plano del fabricante: implantación de equipos","sheet":"LHD2609-GD01000 · espacio modelo","date":"2026-04-30","componentSourceHandles":["7098A"]} | Submalla de triángulos existentes; no hay nueva posición ni nuevas caras. | Cotas globales del conjunto conservadas aparte; las dimensiones de esta ficha son de la submalla. | Coordinación del conjunto padre; anclaje directo individual no acreditado. | Superficie y volumen geométricos brutos; no constituyen cantidades netas de obra, material o fabricación. | Plano general y dimensiones globales de WT3001B; no se asignan esas dimensiones globales a este componente. | ["7098A"] | 1 | no | Submalla exacta; interpretación funcional y cotas parciales provisionales.
Torre de refrigeración WT3001B · Pala de ventilador 6 · contorno CAD | Componente de equipo · cuerpo o accesorio | Plano del fabricante: implantación de equipos · referencia E7 | 0.748145 | 0.186061 | 0.04 | 291.62 | 291.66 | 0.189829 | 0.002482 | Apoyo relativo +2.000 m; cero absoluto provisional | Componente de equipo · cuerpo o accesorio | equipmentComponent | {"name":"No especificado","source":"Sin especificación de material en la documentación revisada","status":"unknown"} | {"documented":[{"label":"Referencia dimensional del conjunto","value":"Plano general y dimensiones globales de WT3001B; no se asignan esas dimensiones globales a este componente.","unit":"","source":"EQ-IMPLANTACION-20260430 · LHD2609-GD01000 · espacio modelo","status":"referencia_del_conjunto"}],"geometry":[{"label":"Extensión de la malla en X","value":0.748145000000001,"unit":"m","source":"Geometría releída del IFC; datum absoluto de proceso provisional","status":"derivado"},{"label":"Extensión de la malla en Y","value":0.18606100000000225,"unit":"m","source":"Geometría releída del IFC; datum absoluto de proceso provisional","status":"derivado"},{"label":"Extensión de la malla en Z","value":0.040000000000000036,"unit":"m","source":"Geometría releída del IFC; datum absoluto de proceso provisional","status":"derivado"},{"label":"Cota inferior de visualización","value":291.62,"unit":"m","source":"Geometría releída del IFC; datum absoluto de proceso provisional","status":"derivado"},{"label":"Cota superior de visualización","value":291.66,"unit":"m","source":"Geometría releída del IFC; datum absoluto de proceso provisional","status":"derivado"}],"notes":["Las dimensiones del equipo completo se conservan en parentEquipmentDimensions.","Las extensiones en X/Y son de los ejes del modelo y no sustituyen cotas locales de fabricación.","No se infieren espesores de chapa, tolerancias ni dimensiones de piezas a partir de la partición."]} | {"documentId":"EQ-IMPLANTACION-20260430","title":"Plano del fabricante: implantación de equipos","sheet":"LHD2609-GD01000 · espacio modelo","date":"2026-04-30","componentSourceHandles":["709A0"]} | {"horizontalStatus":"derivado_del_conjunto","verticalStatus":"derivado_del_conjunto","coordinateSystem":"model_local_m","parentEquipmentId":"WT3001B","transformApplied":false,"note":"Coordenadas copiadas exactamente del equipo coordinado; no se ha movido, girado, elevado ni reescalado este componente.","foundationRelationship":"El apoyo y las cotas de instalación se documentan para el conjunto padre. Esta submalla no acredita un anclaje directo.","meshMinimumAbsoluteElevationM":291.62,"assemblyPlacementField":"parentEquipmentPositioning"} | ["Componente separado de una reconstrucción documental del conjunto. Las alturas y detalles parciales conservan las limitaciones del fabricante registradas en parentEquipmentIssues.","Esta representación exterior no crea una chapa hueca ni añade componentes internos no documentados.","La pertenencia al conjunto no demuestra apoyo o anclaje directo a la cimentación."] | {"source":{"documentId":"EQ-IMPLANTACION-20260430","title":"Plano del fabricante: implantación de equipos","sheet":"LHD2609-GD01000 · espacio modelo","date":"2026-04-30","componentSourceHandles":["709A0"]},"sourcePartId":"WT3001B--blade-06","sourceHandles":["709A0"],"partCount":1,"partsAreBOM":false,"status":"Submalla exacta; interpretación funcional y cotas parciales provisionales."} | {"boundingBoxM":{"min":[38.601979,47.757222,6.62],"max":[39.350124,47.943283,6.66]},"extentsM":[0.748145,0.186061,0.04],"meshSurfaceM2":0.189829,"meshVolumeM3":0.002482,"closedSolid":true,"basis":"Geometría de coordinación. Los volúmenes de referencia y subcomponentes no son cantidades de material ni componentes de fabricación certificados."} | {"documentId":"LHD2609-JG00100-20260904","title":"Cimentaciones y pedestales de equipos · revisión recibida 04/09/2026","date":"2026-09-04","sheet":"9 / 9-9 / 9A-9A","sourceHandles":["2483D","24841","24772"]} | equipment | {"id":"equipment","name":"Equipos"} | {"profileId":"equipment_silver","name":"Intercambiador · metal gris provisional","materialName":"No especificado","physicalMaterialStatus":"unknown","physicalMaterialSource":"Sin especificación de material en la documentación revisada","appearanceStatus":"provisional","appearanceBasis":"Referencia visual de fotografías públicas de Jinhong Gas / fabricante. Apariencia provisional para coordinación; fotografías oficiales pueden orientar el color, pero no acreditan el material, el acabado ni el equipo concreto.","appearanceReferences":["jinhong-official-asu"],"note":"El perfil visual no confirma material, grado ni acabado del componente."} | {"status":"componente_independiente","note":"Objeto independiente seleccionable. Las caras se asignan una sola vez entre todos los componentes del conjunto.","parentEquipmentId":"WT3001B","isAssemblyIdentityCarrier":false} | {"elementId":"WT3001B--blade-06","ifcGuid":"0DZPJqnPTRH9NjhmSGc$22","ifcClass":"IfcBuildingElementProxy","buildingId":"process_plant","buildingName":"Planta de proceso","sourceDocumentId":"EQ-IMPLANTACION-20260430","sourceRepresentationKind":"equipmentComponent"} | {"layerId":"equipment","layerName":"Equipos","role":"Componente de equipo · cuerpo o accesorio","basis":"Clasificación por función del elemento; no modifica las especificaciones documentales."} | {"profileId":"equipment_silver","name":"Intercambiador · metal gris provisional","status":"provisional","basis":"Referencia visual de fotografías públicas de Jinhong Gas / fabricante. Apariencia provisional para coordinación; fotografías oficiales pueden orientar el color, pero no acreditan el material, el acabado ni el equipo concreto.","physicalMaterialUnchanged":true} | Equipos | No especificado | Equipos | Intercambiador · metal gris provisional | provisional | WT3001B--blade-06 | ["Componente separado de una reconstrucción documental del conjunto. Las alturas y detalles parciales conservan las limitaciones del fabricante registradas en parentEquipmentIssues.","Esta representación exterior no crea una chapa hueca ni añade componentes internos no documentados.","La pertenencia al conjunto no demuestra apoyo o anclaje directo a la cimentación."] | Geometría de coordinación. Los volúmenes de referencia y subcomponentes no son cantidades de material ni componentes de fabricación certificados. | Sin especificación de material en la documentación revisada | {"documentId":"EQ-IMPLANTACION-20260430","title":"Plano del fabricante: implantación de equipos","sheet":"LHD2609-GD01000 · espacio modelo","date":"2026-04-30","componentSourceHandles":["709A0"]} | yes | equipment_silver | [0.68,0.72,0.75] | 0.38 | 0.7 | Referencia visual de fotografías públicas de Jinhong Gas / fabricante. Apariencia provisional para coordinación; fotografías oficiales pueden orientar el color, pero no acreditan el material, el acabado ni el equipo concreto. | La apariencia no certifica el material físico ni el acabado de fabricación. | BIM · Equipos | WT3001B | Torre de refrigeración WT3001B | IfcCoolingTower | {"documented":[{"label":"Dimensión X local del contorno CAD","value":5.85,"unit":"m","source":"EQ-CARGAS-20260825 · contorno CAD · handles 524","status":"derivado"},{"label":"Dimensión Y local del contorno CAD","value":2.14,"unit":"m","source":"EQ-CARGAS-20260825 · contorno CAD · handles 524","status":"derivado"},{"label":"Altura acotada","value":3.7,"unit":"m","source":"EQ-CARGAS-20260825 · handle 2659","status":"documentado"},{"label":"Cota relativa de la superficie de apoyo","value":2.0,"unit":"m","source":"LHD2609-JG00100-20260904 · sección 9 / 9-9 / 9A-9A · 2483D, 24841, 24772","status":"documentado"}],"geometry":[{"label":"Extensión de la malla en X","value":6.086960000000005,"unit":"m","source":"Geometría releída del IFC; datum absoluto de proceso provisional","status":"derivado"},{"label":"Extensión de la malla en Y","value":2.9168499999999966,"unit":"m","source":"Geometría releída del IFC; datum absoluto de proceso provisional","status":"derivado"},{"label":"Extensión de la malla en Z","value":3.6999999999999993,"unit":"m","source":"Geometría releída del IFC; datum absoluto de proceso provisional","status":"derivado"},{"label":"Cota inferior de visualización","value":288.1,"unit":"m","source":"Geometría releída del IFC; datum absoluto de proceso provisional","status":"derivado"},{"label":"Cota superior de visualización","value":291.8,"unit":"m","source":"Geometría releída del IFC; datum absoluto de proceso provisional","status":"derivado"}],"notes":["Las extensiones de la malla se miden en los ejes del proyecto tras el giro de implantación; no sustituyen las dimensiones locales del fabricante.","La envolvente, su volumen y los espesores de visualización no son volúmenes de material ni cantidades de compra, construcción o fabricación.","Las dimensiones documentadas distinguen cotas explícitas y medidas extraídas de contornos CAD; las dimensiones geométricas describen únicamente la malla publicada.","Las extensiones de la malla refinada y las dimensiones documentadas del contorno o bastidor tienen distinto alcance; las cotas parciales del detalle son provisionales."]} | {"Estado de la planta":"Derivado del CAD y del giro de implantación","Nivel relativo del apoyo (m)":2.0,"Estado del nivel relativo":"Documentado en el plano de cimentaciones","Cero absoluto de visualización (m)":286.1,"Estado del cero absoluto":"Provisional","Cota del apoyo de visualización (m)":288.1,"Desplazamiento aplicado a la malla (m)":2.0000000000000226,"Criterio":"Nivel de apoyo relativo documentado. Se adopta el cero de proceso a 286,10 m solo para visualización; la equivalencia absoluta no está confirmada. No se añade un espesor de montaje sin cota del fabricante."} | ["La masa de 5 750 kg por unidad es el reparto uniforme de 23 000 kg del conjunto; confirmar el reparto real de cargas. Barandillas y sombreretes no se detallan.","El detalle de abril presenta una célula de 5,85 × 2,20 m; el contorno de agosto es de 5,85 × 2,14 m. Se usa el contorno de agosto. El ventilador se traslada al nuevo centro sin alterar su diámetro ni sus palas.","Las cotas intermedias 3,20 / 3,40 / 3,52 / 3,56 m no aparecen acotadas en el fabricante.","Espesor de palas de 0,04 m y altura del aro de 0,30 m: hipótesis de visualización.","La sección y altura reales de la estructura y de los paneles permanecen sin confirmar.","Los 25 pilares DZ9 terminan en +2,000; los cinco muros transversales terminan en +1,000. La instalación se asocia a los pilares superiores. El plano conserva -2,200 frente al fondo -2,000 de la sección.","El cero absoluto de la revisión no está definido; 286,10 m sigue siendo una hipótesis de coordinación.","Se alinea el punto inferior del conjunto del equipo, incluidos los pies ya representados, con la superficie de apoyo terminada; no se añade un espesor de calzos, placa o grout del fabricante no documentado."] | {"revision":"Detalle en planta de 2026-04-30 coordinado de forma preliminar con envolventes y alturas de 2026-08-25","status":"provisional","verticalRule":"Altura total documentada: 3,70 m. Distribución conceptual: cuerpo 0–3,20 m; plataforma superior 3,20–3,40 m; aro del ventilador 3,40–3,70 m; palas 3,52–3,56 m.","partCount":12,"source":{"documentId":"EQ-IMPLANTACION-20260430","title":"Plano del fabricante: implantación de equipos","sheet":"LHD2609-GD01000 · espacio modelo","date":"2026-04-30"},"heightSource":{"documentId":"EQ-CARGAS-20260825","title":"Plano del fabricante: cargas de equipos","sheet":"Espacio modelo","date":"2026-08-25"},"unconfirmedDimensions":["Las cotas intermedias 3,20 / 3,40 / 3,52 / 3,56 m no aparecen acotadas en el fabricante.","Espesor de palas de 0,04 m y altura del aro de 0,30 m: hipótesis de visualización.","La sección y altura reales de la estructura y de los paneles permanecen sin confirmar."],"quantityUse":"Magnitudes de la geometría representada; no son cantidades de material, obra, compra, capacidad útil ni fabricación. En geometrías compuestas se suman superficies y volúmenes de partes y pueden existir solapes no depurados.","partsAreBOM":false} | equipment_component | {"min":[36.44488,46.344292,3.1],"max":[42.53184,49.261142,6.8]} | {"boundingBoxM":{"min":[36.44488,46.344292,3.1],"max":[42.53184,49.261142,6.8]},"extentsM":[6.086960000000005,2.9168499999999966,3.6999999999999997],"meshSurfaceM2":106.9519119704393,"meshVolumeM3":42.21444876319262,"closedSolid":true,"windingConsistent":true,"basis":"Submalla exacta de los triángulos del modelo IFC coordinado; separación de componentes sin transformación ni retesselación."} | ["Las cotas intermedias 3,20 / 3,40 / 3,52 / 3,56 m no aparecen acotadas en el fabricante.","Espesor de palas de 0,04 m y altura del aro de 0,30 m: hipótesis de visualización.","La sección y altura reales de la estructura y de los paneles permanecen sin confirmar.","La separación gráfica no aporta cotas de fabricación ni identifica piezas internas no documentadas.","Los materiales y acabados permanecen provisionales; las fotografías públicas solo orientan la apariencia."] | {"id":"WT3001B--blade-06","sourcePartId":"WT3001B--blade-06","name":"Pala de ventilador 6 · contorno CAD","role":"equipment_component","classificationStatus":"provisional","classificationBasis":"Rol del subvolumen gráfico según el activo de detalle; identidad de fabricación no confirmada.","parentEquipmentId":"WT3001B","parentEquipmentGuid":"3QfAgBB2zPsvSc6AB8$nne","isAssemblyIdentityCarrier":false,"sourceFaceRange":[2432,2452],"sourceCurrentFaceIndices":[2432,2433,2434,2435,2436,2437,2438,2439,2440,2441,2442,2443,2444,2445,2446,2447,2448,2449,2450,2451],"sourceMeshSha256":"7b60c904c9d84d22fded9be34af09a09a9c198ec8e75e61902634d5e4064c761","sourceVertexIndices":[1228,1229,1230,1231,1232,1233,1234,1235,1236,1237,1238,1239],"separationMethod":"Partición exacta de triángulos existentes; coordenadas y orientación de caras conservadas.","quantityUse":"Magnitudes geométricas del subvolumen; no son cantidades netas de material, fabricación, suministro o capacidad."} | {"id":"WT3001B","name":"Torre de refrigeración WT3001B","relationship":"decomposed_component","parentShapeMeaning":"La forma del objeto que conserva el ID del equipo es únicamente su componente principal; el conjunto completo requiere sus hijos."} | {"kind":"through_parent","parentEquipmentId":"WT3001B","directAnchorageVerified":false,"note":"La relación del conjunto con cimentaciones se conserva en el objeto que mantiene el ID del equipo; no se atribuye fijación directa a cada subcomponente."} | Documento de implantación y apoyo del conjunto padre; no acredita fijación individual de este componente. | WT3001B--blade-06 | Pala de ventilador 6 · contorno CAD | Equipos | unknown | equipment_silver | {"documentId":"EQ-IMPLANTACION-20260430","title":"Plano del fabricante: implantación de equipos","sheet":"LHD2609-GD01000 · espacio modelo","date":"2026-04-30","componentSourceHandles":["709A0"]} | Submalla de triángulos existentes; no hay nueva posición ni nuevas caras. | Cotas globales del conjunto conservadas aparte; las dimensiones de esta ficha son de la submalla. | Coordinación del conjunto padre; anclaje directo individual no acreditado. | Superficie y volumen geométricos brutos; no constituyen cantidades netas de obra, material o fabricación. | Plano general y dimensiones globales de WT3001B; no se asignan esas dimensiones globales a este componente. | ["709A0"] | 1 | no | Submalla exacta; interpretación funcional y cotas parciales provisionales.
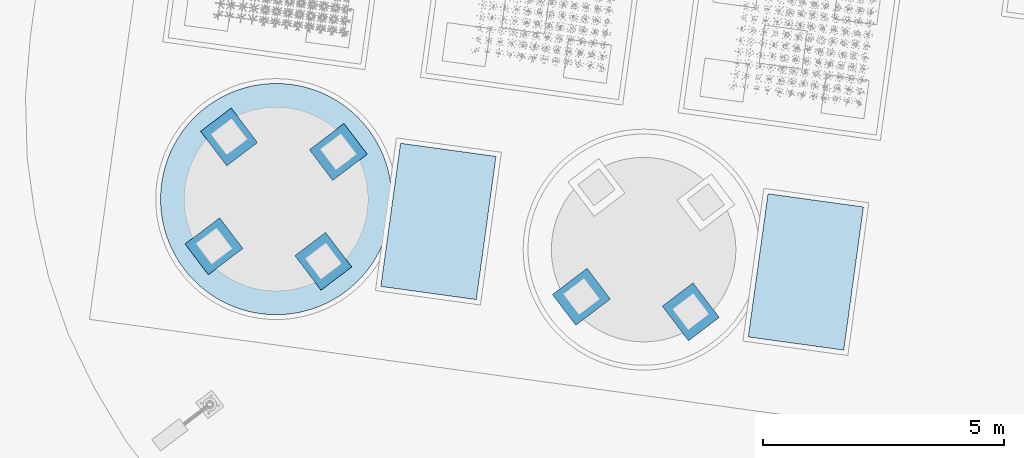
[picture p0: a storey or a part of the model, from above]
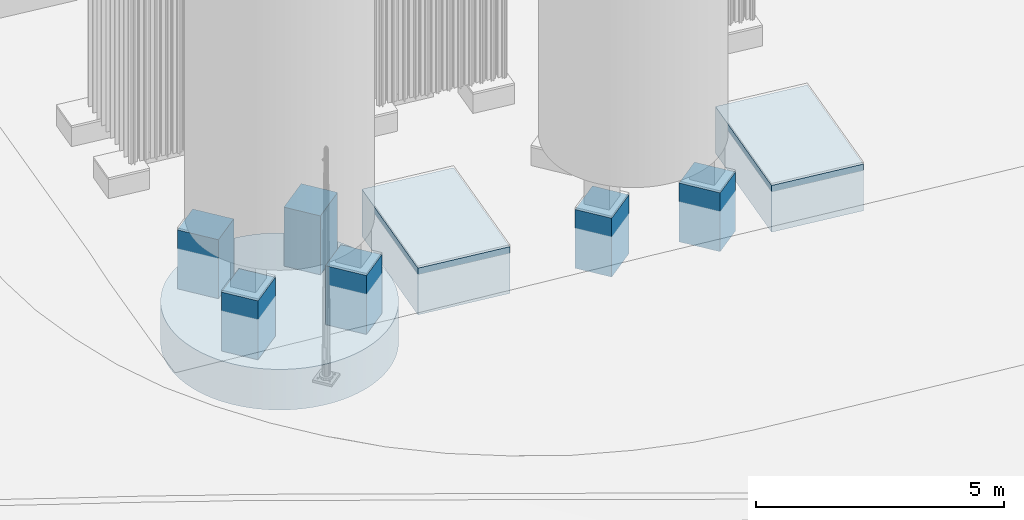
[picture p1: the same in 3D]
Properties of the parts of a building model (IFC4), part 12 of 134

# IfcBuildingElementProxy (140)
Name | Description | Document | Extensión de la malla en X (m) = ExtensionX (m) | Extensión de la malla en Y (m) = ExtensionY (m) | Extensión de la malla en Z (m) = ExtensionZ (m) | Cota inferior de visualización (m) | Cota superior de visualización (m) | SuperficieDeLaMalla (m2) | VolumenGeometrico (m3) | level | category = Categoria = Funcion | representationKind | material | dimensions | JH_InformacionBIM, source = DocumentoFuente | positioning = PosicionYEstado | issues | detailGeometry | geometryMetrics | installationSource | layerId = IdentificadorCapa | visualLayer | materialAppearance | componentSeparation | visualizationIdentity | classification | appearance | Disciplina | Material | Capa BIM = NombreCapa | Acabado de visualización = Acabado | Estado del acabado = Estado | Identificador | JH_Trazabilidad, IncidenciasPendientes | UsoDeLasMagnitudes | JH_EvidenciaDeMaterial, source | JH_DetalleGeometrico, source | VisibilidadInicial | Perfil | ColorRGB | Rugosidad | Metallicidad | Referencia | Nota | Group | parentEquipmentId = Identificador del equipo padre | parentEquipmentName = Equipo padre | parentEquipmentIfcClass | parentEquipmentDimensions | parentEquipmentPositioning | parentEquipmentIssues | parentEquipmentDetail | componentRole = Rol del componente | assemblyBBox | assemblyGeometryMetrics | manufacturerDetailsPending | component | assembly | foundationRelationship | installationSourceScope | Identificador del elemento = sourcePartId | Componente | Capa de visualización | Estado del material | Perfil visual del material | Fuente del componente | Criterio de partición | Criterio de las dimensiones | Relación con cimentaciones | Aplicabilidad de las mediciones | Referencia dimensional del conjunto | sourceHandles | partCount | partsAreBOM | status
Torre de refrigeración WT3001B · Envolvente del buje del ventilador | Componente de equipo · cuerpo o accesorio | Plano del fabricante: implantación de equipos · referencia E7 | 0.36437 | 0.36437 | 0.25 | 291.55 | 291.8 | 0.49465 | 0.026061 | Apoyo relativo +2.000 m; cero absoluto provisional | Componente de equipo · cuerpo o accesorio | equipmentComponent | {"name":"No especificado","source":"Sin especificación de material en la documentación revisada","status":"unknown"} | {"documented":[{"label":"Referencia dimensional del conjunto","value":"Plano general y dimensiones globales de WT3001B; no se asignan esas dimensiones globales a este componente.","unit":"","source":"EQ-IMPLANTACION-20260430 · LHD2609-GD01000 · espacio modelo","status":"referencia_del_conjunto"}],"geometry":[{"label":"Extensión de la malla en X","value":0.36436999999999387,"unit":"m","source":"Geometría releída del IFC; datum absoluto de proceso provisional","status":"derivado"},{"label":"Extensión de la malla en Y","value":0.36437000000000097,"unit":"m","source":"Geometría releída del IFC; datum absoluto de proceso provisional","status":"derivado"},{"label":"Extensión de la malla en Z","value":0.25,"unit":"m","source":"Geometría releída del IFC; datum absoluto de proceso provisional","status":"derivado"},{"label":"Cota inferior de visualización","value":291.55,"unit":"m","source":"Geometría releída del IFC; datum absoluto de proceso provisional","status":"derivado"},{"label":"Cota superior de visualización","value":291.8,"unit":"m","source":"Geometría releída del IFC; datum absoluto de proceso provisional","status":"derivado"}],"notes":["Las dimensiones del equipo completo se conservan en parentEquipmentDimensions.","Las extensiones en X/Y son de los ejes del modelo y no sustituyen cotas locales de fabricación.","No se infieren espesores de chapa, tolerancias ni dimensiones de piezas a partir de la partición."]} | {"documentId":"EQ-IMPLANTACION-20260430","title":"Plano del fabricante: implantación de equipos","sheet":"LHD2609-GD01000 · espacio modelo","date":"2026-04-30","componentSourceHandles":["709C2"]} | {"horizontalStatus":"derivado_del_conjunto","verticalStatus":"derivado_del_conjunto","coordinateSystem":"model_local_m","parentEquipmentId":"WT3001B","transformApplied":false,"note":"Coordenadas copiadas exactamente del equipo coordinado; no se ha movido, girado, elevado ni reescalado este componente.","foundationRelationship":"El apoyo y las cotas de instalación se documentan para el conjunto padre. Esta submalla no acredita un anclaje directo.","meshMinimumAbsoluteElevationM":291.55,"assemblyPlacementField":"parentEquipmentPositioning"} | ["Componente separado de una reconstrucción documental del conjunto. Las alturas y detalles parciales conservan las limitaciones del fabricante registradas en parentEquipmentIssues.","Esta representación exterior no crea una chapa hueca ni añade componentes internos no documentados.","La pertenencia al conjunto no demuestra apoyo o anclaje directo a la cimentación."] | {"source":{"documentId":"EQ-IMPLANTACION-20260430","title":"Plano del fabricante: implantación de equipos","sheet":"LHD2609-GD01000 · espacio modelo","date":"2026-04-30","componentSourceHandles":["709C2"]},"sourcePartId":"WT3001B--fan-hub","sourceHandles":["709C2"],"partCount":1,"partsAreBOM":false,"status":"Submalla exacta; interpretación funcional y cotas parciales provisionales."} | {"boundingBoxM":{"min":[39.306175,47.620532,6.55],"max":[39.670545,47.984902,6.8]},"extentsM":[0.36437,0.36437,0.25],"meshSurfaceM2":0.49465,"meshVolumeM3":0.026061,"closedSolid":true,"basis":"Geometría de coordinación. Los volúmenes de referencia y subcomponentes no son cantidades de material ni componentes de fabricación certificados."} | {"documentId":"LHD2609-JG00100-20260904","title":"Cimentaciones y pedestales de equipos · revisión recibida 04/09/2026","date":"2026-09-04","sheet":"9 / 9-9 / 9A-9A","sourceHandles":["2483D","24841","24772"]} | equipment | {"id":"equipment","name":"Equipos"} | {"profileId":"equipment_silver","name":"Intercambiador · metal gris provisional","materialName":"No especificado","physicalMaterialStatus":"unknown","physicalMaterialSource":"Sin especificación de material en la documentación revisada","appearanceStatus":"provisional","appearanceBasis":"Referencia visual de fotografías públicas de Jinhong Gas / fabricante. Apariencia provisional para coordinación; fotografías oficiales pueden orientar el color, pero no acreditan el material, el acabado ni el equipo concreto.","appearanceReferences":["jinhong-official-asu"],"note":"El perfil visual no confirma material, grado ni acabado del componente."} | {"status":"componente_independiente","note":"Objeto independiente seleccionable. Las caras se asignan una sola vez entre todos los componentes del conjunto.","parentEquipmentId":"WT3001B","isAssemblyIdentityCarrier":false} | {"elementId":"WT3001B--fan-hub","ifcGuid":"3krKWXm$HPmBGDrCy6IJh1","ifcClass":"IfcBuildingElementProxy","buildingId":"process_plant","buildingName":"Planta de proceso","sourceDocumentId":"EQ-IMPLANTACION-20260430","sourceRepresentationKind":"equipmentComponent"} | {"layerId":"equipment","layerName":"Equipos","role":"Componente de equipo · cuerpo o accesorio","basis":"Clasificación por función del elemento; no modifica las especificaciones documentales."} | {"profileId":"equipment_silver","name":"Intercambiador · metal gris provisional","status":"provisional","basis":"Referencia visual de fotografías públicas de Jinhong Gas / fabricante. Apariencia provisional para coordinación; fotografías oficiales pueden orientar el color, pero no acreditan el material, el acabado ni el equipo concreto.","physicalMaterialUnchanged":true} | Equipos | No especificado | Equipos | Intercambiador · metal gris provisional | provisional | WT3001B--fan-hub | ["Componente separado de una reconstrucción documental del conjunto. Las alturas y detalles parciales conservan las limitaciones del fabricante registradas en parentEquipmentIssues.","Esta representación exterior no crea una chapa hueca ni añade componentes internos no documentados.","La pertenencia al conjunto no demuestra apoyo o anclaje directo a la cimentación."] | Geometría de coordinación. Los volúmenes de referencia y subcomponentes no son cantidades de material ni componentes de fabricación certificados. | Sin especificación de material en la documentación revisada | {"documentId":"EQ-IMPLANTACION-20260430","title":"Plano del fabricante: implantación de equipos","sheet":"LHD2609-GD01000 · espacio modelo","date":"2026-04-30","componentSourceHandles":["709C2"]} | yes | equipment_silver | [0.68,0.72,0.75] | 0.38 | 0.7 | Referencia visual de fotografías públicas de Jinhong Gas / fabricante. Apariencia provisional para coordinación; fotografías oficiales pueden orientar el color, pero no acreditan el material, el acabado ni el equipo concreto. | La apariencia no certifica el material físico ni el acabado de fabricación. | BIM · Equipos | WT3001B | Torre de refrigeración WT3001B | IfcCoolingTower | {"documented":[{"label":"Dimensión X local del contorno CAD","value":5.85,"unit":"m","source":"EQ-CARGAS-20260825 · contorno CAD · handles 524","status":"derivado"},{"label":"Dimensión Y local del contorno CAD","value":2.14,"unit":"m","source":"EQ-CARGAS-20260825 · contorno CAD · handles 524","status":"derivado"},{"label":"Altura acotada","value":3.7,"unit":"m","source":"EQ-CARGAS-20260825 · handle 2659","status":"documentado"},{"label":"Cota relativa de la superficie de apoyo","value":2.0,"unit":"m","source":"LHD2609-JG00100-20260904 · sección 9 / 9-9 / 9A-9A · 2483D, 24841, 24772","status":"documentado"}],"geometry":[{"label":"Extensión de la malla en X","value":6.086960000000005,"unit":"m","source":"Geometría releída del IFC; datum absoluto de proceso provisional","status":"derivado"},{"label":"Extensión de la malla en Y","value":2.9168499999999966,"unit":"m","source":"Geometría releída del IFC; datum absoluto de proceso provisional","status":"derivado"},{"label":"Extensión de la malla en Z","value":3.6999999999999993,"unit":"m","source":"Geometría releída del IFC; datum absoluto de proceso provisional","status":"derivado"},{"label":"Cota inferior de visualización","value":288.1,"unit":"m","source":"Geometría releída del IFC; datum absoluto de proceso provisional","status":"derivado"},{"label":"Cota superior de visualización","value":291.8,"unit":"m","source":"Geometría releída del IFC; datum absoluto de proceso provisional","status":"derivado"}],"notes":["Las extensiones de la malla se miden en los ejes del proyecto tras el giro de implantación; no sustituyen las dimensiones locales del fabricante.","La envolvente, su volumen y los espesores de visualización no son volúmenes de material ni cantidades de compra, construcción o fabricación.","Las dimensiones documentadas distinguen cotas explícitas y medidas extraídas de contornos CAD; las dimensiones geométricas describen únicamente la malla publicada.","Las extensiones de la malla refinada y las dimensiones documentadas del contorno o bastidor tienen distinto alcance; las cotas parciales del detalle son provisionales."]} | {"Estado de la planta":"Derivado del CAD y del giro de implantación","Nivel relativo del apoyo (m)":2.0,"Estado del nivel relativo":"Documentado en el plano de cimentaciones","Cero absoluto de visualización (m)":286.1,"Estado del cero absoluto":"Provisional","Cota del apoyo de visualización (m)":288.1,"Desplazamiento aplicado a la malla (m)":2.0000000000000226,"Criterio":"Nivel de apoyo relativo documentado. Se adopta el cero de proceso a 286,10 m solo para visualización; la equivalencia absoluta no está confirmada. No se añade un espesor de montaje sin cota del fabricante."} | ["La masa de 5 750 kg por unidad es el reparto uniforme de 23 000 kg del conjunto; confirmar el reparto real de cargas. Barandillas y sombreretes no se detallan.","El detalle de abril presenta una célula de 5,85 × 2,20 m; el contorno de agosto es de 5,85 × 2,14 m. Se usa el contorno de agosto. El ventilador se traslada al nuevo centro sin alterar su diámetro ni sus palas.","Las cotas intermedias 3,20 / 3,40 / 3,52 / 3,56 m no aparecen acotadas en el fabricante.","Espesor de palas de 0,04 m y altura del aro de 0,30 m: hipótesis de visualización.","La sección y altura reales de la estructura y de los paneles permanecen sin confirmar.","Los 25 pilares DZ9 terminan en +2,000; los cinco muros transversales terminan en +1,000. La instalación se asocia a los pilares superiores. El plano conserva -2,200 frente al fondo -2,000 de la sección.","El cero absoluto de la revisión no está definido; 286,10 m sigue siendo una hipótesis de coordinación.","Se alinea el punto inferior del conjunto del equipo, incluidos los pies ya representados, con la superficie de apoyo terminada; no se añade un espesor de calzos, placa o grout del fabricante no documentado."] | {"revision":"Detalle en planta de 2026-04-30 coordinado de forma preliminar con envolventes y alturas de 2026-08-25","status":"provisional","verticalRule":"Altura total documentada: 3,70 m. Distribución conceptual: cuerpo 0–3,20 m; plataforma superior 3,20–3,40 m; aro del ventilador 3,40–3,70 m; palas 3,52–3,56 m.","partCount":12,"source":{"documentId":"EQ-IMPLANTACION-20260430","title":"Plano del fabricante: implantación de equipos","sheet":"LHD2609-GD01000 · espacio modelo","date":"2026-04-30"},"heightSource":{"documentId":"EQ-CARGAS-20260825","title":"Plano del fabricante: cargas de equipos","sheet":"Espacio modelo","date":"2026-08-25"},"unconfirmedDimensions":["Las cotas intermedias 3,20 / 3,40 / 3,52 / 3,56 m no aparecen acotadas en el fabricante.","Espesor de palas de 0,04 m y altura del aro de 0,30 m: hipótesis de visualización.","La sección y altura reales de la estructura y de los paneles permanecen sin confirmar."],"quantityUse":"Magnitudes de la geometría representada; no son cantidades de material, obra, compra, capacidad útil ni fabricación. En geometrías compuestas se suman superficies y volúmenes de partes y pueden existir solapes no depurados.","partsAreBOM":false} | equipment_component | {"min":[36.44488,46.344292,3.1],"max":[42.53184,49.261142,6.8]} | {"boundingBoxM":{"min":[36.44488,46.344292,3.1],"max":[42.53184,49.261142,6.8]},"extentsM":[6.086960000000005,2.9168499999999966,3.6999999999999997],"meshSurfaceM2":106.9519119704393,"meshVolumeM3":42.21444876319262,"closedSolid":true,"windingConsistent":true,"basis":"Submalla exacta de los triángulos del modelo IFC coordinado; separación de componentes sin transformación ni retesselación."} | ["Las cotas intermedias 3,20 / 3,40 / 3,52 / 3,56 m no aparecen acotadas en el fabricante.","Espesor de palas de 0,04 m y altura del aro de 0,30 m: hipótesis de visualización.","La sección y altura reales de la estructura y de los paneles permanecen sin confirmar.","La separación gráfica no aporta cotas de fabricación ni identifica piezas internas no documentadas.","Los materiales y acabados permanecen provisionales; las fotografías públicas solo orientan la apariencia."] | {"id":"WT3001B--fan-hub","sourcePartId":"WT3001B--fan-hub","name":"Envolvente del buje del ventilador","role":"equipment_component","classificationStatus":"provisional","classificationBasis":"Rol del subvolumen gráfico según el activo de detalle; identidad de fabricación no confirmada.","parentEquipmentId":"WT3001B","parentEquipmentGuid":"3QfAgBB2zPsvSc6AB8$nne","isAssemblyIdentityCarrier":false,"sourceFaceRange":[2452,2960],"sourceCurrentFaceIndices":[2452,2453,2454,2455,2456,2457,2458,2459,2460,2461,2462,2463,2464,2465,2466,2467,2468,2469,2470,2471,2472,2473,2474,2475,2476,2477,2478,2479,2480,2481,2482,2483,2484,2485,2486,2487,2488,2489,2490,2491,2492,2493,2494,2495,2496,2497,2498,2499,2500,2501,2502,2503,2504,2505,2506,2507,2508,2509,2510,2511,2512,2513,2514,2515,2516,2517,2518,2519,2520,2521,2522,2523,2524,2525,2526,2527,2528,2529,2530,2531,2532,2533,2534,2535,2536,2537,2538,2539,2540,2541,2542,2543,2544,2545,2546,2547,2548,2549,2550,2551,2552,2553,2554,2555,2556,2557,2558,2559,2560,2561,2562,2563,2564,2565,2566,2567,2568,2569,2570,2571,2572,2573,2574,2575,2576,2577,2578,2579,2580,2581,2582,2583,2584,2585,2586,2587,2588,2589,2590,2591,2592,2593,2594,2595,2596,2597,2598,2599,2600,2601,2602,2603,2604,2605,2606,2607,2608,2609,2610,2611,2612,2613,2614,2615,2616,2617,2618,2619,2620,2621,2622,2623,2624,2625,2626,2627,2628,2629,2630,2631,2632,2633,2634,2635,2636,2637,2638,2639,2640,2641,2642,2643,2644,2645,2646,2647,2648,2649,2650,2651,2652,2653,2654,2655,2656,2657,2658,2659,2660,2661,2662,2663,2664,2665,2666,2667,2668,2669,2670,2671,2672,2673,2674,2675,2676,2677,2678,2679,2680,2681,2682,2683,2684,2685,2686,2687,2688,2689,2690,2691,2692,2693,2694,2695,2696,2697,2698,2699,2700,2701,2702,2703,2704,2705,2706,2707,2708,2709,2710,2711,2712,2713,2714,2715,2716,2717,2718,2719,2720,2721,2722,2723,2724,2725,2726,2727,2728,2729,2730,2731,2732,2733,2734,2735,2736,2737,2738,2739,2740,2741,2742,2743,2744,2745,2746,2747,2748,2749,2750,2751,2752,2753,2754,2755,2756,2757,2758,2759,2760,2761,2762,2763,2764,2765,2766,2767,2768,2769,2770,2771,2772,2773,2774,2775,2776,2777,2778,2779,2780,2781,2782,2783,2784,2785,2786,2787,2788,2789,2790,2791,2792,2793,2794,2795,2796,2797,2798,2799,2800,2801,2802,2803,2804,2805,2806,2807,2808,2809,2810,2811,2812,2813,2814,2815,2816,2817,2818,2819,2820,2821,2822,2823,2824,2825,2826,2827,2828,2829,2830,2831,2832,2833,2834,2835,2836,2837,2838,2839,2840,2841,2842,2843,2844,2845,2846,2847,2848,2849,2850,2851,2852,2853,2854,2855,2856,2857,2858,2859,2860,2861,2862,2863,2864,2865,2866,2867,2868,2869,2870,2871,2872,2873,2874,2875,2876,2877,2878,2879,2880,2881,2882,2883,2884,2885,2886,2887,2888,2889,2890,2891,2892,2893,2894,2895,2896,2897,2898,2899,2900,2901,2902,2903,2904,2905,2906,2907,2908,2909,2910,2911,2912,2913,2914,2915,2916,2917,2918,2919,2920,2921,2922,2923,2924,2925,2926,2927,2928,2929,2930,2931,2932,2933,2934,2935,2936,2937,2938,2939,2940,2941,2942,2943,2944,2945,2946,2947,2948,2949,2950,2951,2952,2953,2954,2955,2956,2957,2958,2959],"sourceMeshSha256":"7b60c904c9d84d22fded9be34af09a09a9c198ec8e75e61902634d5e4064c761","sourceVertexIndices":[1240,1241,1242,1243,1244,1245,1246,1247,1248,1249,1250,1251,1252,1253,1254,1255,1256,1257,1258,1259,1260,1261,1262,1263,1264,1265,1266,1267,1268,1269,1270,1271,1272,1273,1274,1275,1276,1277,1278,1279,1280,1281,1282,1283,1284,1285,1286,1287,1288,1289,1290,1291,1292,1293,1294,1295,1296,1297,1298,1299,1300,1301,1302,1303,1304,1305,1306,1307,1308,1309,1310,1311,1312,1313,1314,1315,1316,1317,1318,1319,1320,1321,1322,1323,1324,1325,1326,1327,1328,1329,1330,1331,1332,1333,1334,1335,1336,1337,1338,1339,1340,1341,1342,1343,1344,1345,1346,1347,1348,1349,1350,1351,1352,1353,1354,1355,1356,1357,1358,1359,1360,1361,1362,1363,1364,1365,1366,1367,1368,1369,1370,1371,1372,1373,1374,1375,1376,1377,1378,1379,1380,1381,1382,1383,1384,1385,1386,1387,1388,1389,1390,1391,1392,1393,1394,1395,1396,1397,1398,1399,1400,1401,1402,1403,1404,1405,1406,1407,1408,1409,1410,1411,1412,1413,1414,1415,1416,1417,1418,1419,1420,1421,1422,1423,1424,1425,1426,1427,1428,1429,1430,1431,1432,1433,1434,1435,1436,1437,1438,1439,1440,1441,1442,1443,1444,1445,1446,1447,1448,1449,1450,1451,1452,1453,1454,1455,1456,1457,1458,1459,1460,1461,1462,1463,1464,1465,1466,1467,1468,1469,1470,1471,1472,1473,1474,1475,1476,1477,1478,1479,1480,1481,1482,1483,1484,1485,1486,1487,1488,1489,1490,1491,1492,1493,1494,1495],"separationMethod":"Partición exacta de triángulos existentes; coordenadas y orientación de caras conservadas.","quantityUse":"Magnitudes geométricas del subvolumen; no son cantidades netas de material, fabricación, suministro o capacidad."} | {"id":"WT3001B","name":"Torre de refrigeración WT3001B","relationship":"decomposed_component","parentShapeMeaning":"La forma del objeto que conserva el ID del equipo es únicamente su componente principal; el conjunto completo requiere sus hijos."} | {"kind":"through_parent","parentEquipmentId":"WT3001B","directAnchorageVerified":false,"note":"La relación del conjunto con cimentaciones se conserva en el objeto que mantiene el ID del equipo; no se atribuye fijación directa a cada subcomponente."} | Documento de implantación y apoyo del conjunto padre; no acredita fijación individual de este componente. | WT3001B--fan-hub | Envolvente del buje del ventilador | Equipos | unknown | equipment_silver | {"documentId":"EQ-IMPLANTACION-20260430","title":"Plano del fabricante: implantación de equipos","sheet":"LHD2609-GD01000 · espacio modelo","date":"2026-04-30","componentSourceHandles":["709C2"]} | Submalla de triángulos existentes; no hay nueva posición ni nuevas caras. | Cotas globales del conjunto conservadas aparte; las dimensiones de esta ficha son de la submalla. | Coordinación del conjunto padre; anclaje directo individual no acreditado. | Superficie y volumen geométricos brutos; no constituyen cantidades netas de obra, material o fabricación. | Plano general y dimensiones globales de WT3001B; no se asignan esas dimensiones globales a este componente. | ["709C2"] | 1 | no | Submalla exacta; interpretación funcional y cotas parciales provisionales.
Torre de refrigeración WT3001B · Montaje lateral indicado en planta | Componente de equipo · cuerpo o accesorio | Plano del fabricante: implantación de equipos · referencia E7 | 0.352925 | 0.340109 | 0.18 | 291.5 | 291.68 | 0.4104 | 0.01701 | Apoyo relativo +2.000 m; cero absoluto provisional | Componente de equipo · cuerpo o accesorio | equipmentComponent | {"name":"No especificado","source":"Sin especificación de material en la documentación revisada","status":"unknown"} | {"documented":[{"label":"Referencia dimensional del conjunto","value":"Plano general y dimensiones globales de WT3001B; no se asignan esas dimensiones globales a este componente.","unit":"","source":"EQ-IMPLANTACION-20260430 · LHD2609-GD01000 · espacio modelo","status":"referencia_del_conjunto"}],"geometry":[{"label":"Extensión de la malla en X","value":0.35292499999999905,"unit":"m","source":"Geometría releída del IFC; datum absoluto de proceso provisional","status":"derivado"},{"label":"Extensión de la malla en Y","value":0.3401089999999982,"unit":"m","source":"Geometría releída del IFC; datum absoluto de proceso provisional","status":"derivado"},{"label":"Extensión de la malla en Z","value":0.17999999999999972,"unit":"m","source":"Geometría releída del IFC; datum absoluto de proceso provisional","status":"derivado"},{"label":"Cota inferior de visualización","value":291.5,"unit":"m","source":"Geometría releída del IFC; datum absoluto de proceso provisional","status":"derivado"},{"label":"Cota superior de visualización","value":291.68,"unit":"m","source":"Geometría releída del IFC; datum absoluto de proceso provisional","status":"derivado"}],"notes":["Las dimensiones del equipo completo se conservan en parentEquipmentDimensions.","Las extensiones en X/Y son de los ejes del modelo y no sustituyen cotas locales de fabricación.","No se infieren espesores de chapa, tolerancias ni dimensiones de piezas a partir de la partición."]} | {"documentId":"EQ-IMPLANTACION-20260430","title":"Plano del fabricante: implantación de equipos","sheet":"LHD2609-GD01000 · espacio modelo","date":"2026-04-30","componentSourceHandles":["7080E"]} | {"horizontalStatus":"derivado_del_conjunto","verticalStatus":"derivado_del_conjunto","coordinateSystem":"model_local_m","parentEquipmentId":"WT3001B","transformApplied":false,"note":"Coordenadas copiadas exactamente del equipo coordinado; no se ha movido, girado, elevado ni reescalado este componente.","foundationRelationship":"El apoyo y las cotas de instalación se documentan para el conjunto padre. Esta submalla no acredita un anclaje directo.","meshMinimumAbsoluteElevationM":291.5,"assemblyPlacementField":"parentEquipmentPositioning"} | ["Componente separado de una reconstrucción documental del conjunto. Las alturas y detalles parciales conservan las limitaciones del fabricante registradas en parentEquipmentIssues.","Esta representación exterior no crea una chapa hueca ni añade componentes internos no documentados.","La pertenencia al conjunto no demuestra apoyo o anclaje directo a la cimentación."] | {"source":{"documentId":"EQ-IMPLANTACION-20260430","title":"Plano del fabricante: implantación de equipos","sheet":"LHD2609-GD01000 · espacio modelo","date":"2026-04-30","componentSourceHandles":["7080E"]},"sourcePartId":"WT3001B--lateral-mount-1","sourceHandles":["7080E"],"partCount":1,"partsAreBOM":false,"status":"Submalla exacta; interpretación funcional y cotas parciales provisionales."} | {"boundingBoxM":{"min":[37.094259,47.937555,6.5],"max":[37.447184,48.277664,6.68]},"extentsM":[0.352925,0.340109,0.18],"meshSurfaceM2":0.4104,"meshVolumeM3":0.01701,"closedSolid":true,"basis":"Geometría de coordinación. Los volúmenes de referencia y subcomponentes no son cantidades de material ni componentes de fabricación certificados."} | {"documentId":"LHD2609-JG00100-20260904","title":"Cimentaciones y pedestales de equipos · revisión recibida 04/09/2026","date":"2026-09-04","sheet":"9 / 9-9 / 9A-9A","sourceHandles":["2483D","24841","24772"]} | equipment | {"id":"equipment","name":"Equipos"} | {"profileId":"equipment_dark_frame","name":"Bastidor metálico · gris oscuro provisional","materialName":"No especificado","physicalMaterialStatus":"unknown","physicalMaterialSource":"Sin especificación de material en la documentación revisada","appearanceStatus":"provisional","appearanceBasis":"Referencia visual de fotografías públicas de Jinhong Gas / fabricante. Apariencia provisional para coordinación; fotografías oficiales pueden orientar el color, pero no acreditan el material, el acabado ni el equipo concreto.","appearanceReferences":["jinhong-official-asu"],"note":"El perfil visual no confirma material, grado ni acabado del componente."} | {"status":"componente_independiente","note":"Objeto independiente seleccionable. Las caras se asignan una sola vez entre todos los componentes del conjunto.","parentEquipmentId":"WT3001B","isAssemblyIdentityCarrier":false} | {"elementId":"WT3001B--lateral-mount-1","ifcGuid":"3H1CcMUP1LVAjsazgWA35P","ifcClass":"IfcBuildingElementProxy","buildingId":"process_plant","buildingName":"Planta de proceso","sourceDocumentId":"EQ-IMPLANTACION-20260430","sourceRepresentationKind":"equipmentComponent"} | {"layerId":"equipment","layerName":"Equipos","role":"Componente de equipo · cuerpo o accesorio","basis":"Clasificación por función del elemento; no modifica las especificaciones documentales."} | {"profileId":"equipment_dark_frame","name":"Bastidor metálico · gris oscuro provisional","status":"provisional","basis":"Referencia visual de fotografías públicas de Jinhong Gas / fabricante. Apariencia provisional para coordinación; fotografías oficiales pueden orientar el color, pero no acreditan el material, el acabado ni el equipo concreto.","physicalMaterialUnchanged":true} | Equipos | No especificado | Equipos | Bastidor metálico · gris oscuro provisional | provisional | WT3001B--lateral-mount-1 | ["Componente separado de una reconstrucción documental del conjunto. Las alturas y detalles parciales conservan las limitaciones del fabricante registradas en parentEquipmentIssues.","Esta representación exterior no crea una chapa hueca ni añade componentes internos no documentados.","La pertenencia al conjunto no demuestra apoyo o anclaje directo a la cimentación."] | Geometría de coordinación. Los volúmenes de referencia y subcomponentes no son cantidades de material ni componentes de fabricación certificados. | Sin especificación de material en la documentación revisada | {"documentId":"EQ-IMPLANTACION-20260430","title":"Plano del fabricante: implantación de equipos","sheet":"LHD2609-GD01000 · espacio modelo","date":"2026-04-30","componentSourceHandles":["7080E"]} | yes | equipment_dark_frame | [0.290196,0.329412,0.34902] | 0.62 | 0.5 | Referencia visual de fotografías públicas de Jinhong Gas / fabricante. Apariencia provisional para coordinación; fotografías oficiales pueden orientar el color, pero no acreditan el material, el acabado ni el equipo concreto. | La apariencia no certifica el material físico ni el acabado de fabricación. | BIM · Equipos | WT3001B | Torre de refrigeración WT3001B | IfcCoolingTower | {"documented":[{"label":"Dimensión X local del contorno CAD","value":5.85,"unit":"m","source":"EQ-CARGAS-20260825 · contorno CAD · handles 524","status":"derivado"},{"label":"Dimensión Y local del contorno CAD","value":2.14,"unit":"m","source":"EQ-CARGAS-20260825 · contorno CAD · handles 524","status":"derivado"},{"label":"Altura acotada","value":3.7,"unit":"m","source":"EQ-CARGAS-20260825 · handle 2659","status":"documentado"},{"label":"Cota relativa de la superficie de apoyo","value":2.0,"unit":"m","source":"LHD2609-JG00100-20260904 · sección 9 / 9-9 / 9A-9A · 2483D, 24841, 24772","status":"documentado"}],"geometry":[{"label":"Extensión de la malla en X","value":6.086960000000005,"unit":"m","source":"Geometría releída del IFC; datum absoluto de proceso provisional","status":"derivado"},{"label":"Extensión de la malla en Y","value":2.9168499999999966,"unit":"m","source":"Geometría releída del IFC; datum absoluto de proceso provisional","status":"derivado"},{"label":"Extensión de la malla en Z","value":3.6999999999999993,"unit":"m","source":"Geometría releída del IFC; datum absoluto de proceso provisional","status":"derivado"},{"label":"Cota inferior de visualización","value":288.1,"unit":"m","source":"Geometría releída del IFC; datum absoluto de proceso provisional","status":"derivado"},{"label":"Cota superior de visualización","value":291.8,"unit":"m","source":"Geometría releída del IFC; datum absoluto de proceso provisional","status":"derivado"}],"notes":["Las extensiones de la malla se miden en los ejes del proyecto tras el giro de implantación; no sustituyen las dimensiones locales del fabricante.","La envolvente, su volumen y los espesores de visualización no son volúmenes de material ni cantidades de compra, construcción o fabricación.","Las dimensiones documentadas distinguen cotas explícitas y medidas extraídas de contornos CAD; las dimensiones geométricas describen únicamente la malla publicada.","Las extensiones de la malla refinada y las dimensiones documentadas del contorno o bastidor tienen distinto alcance; las cotas parciales del detalle son provisionales."]} | {"Estado de la planta":"Derivado del CAD y del giro de implantación","Nivel relativo del apoyo (m)":2.0,"Estado del nivel relativo":"Documentado en el plano de cimentaciones","Cero absoluto de visualización (m)":286.1,"Estado del cero absoluto":"Provisional","Cota del apoyo de visualización (m)":288.1,"Desplazamiento aplicado a la malla (m)":2.0000000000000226,"Criterio":"Nivel de apoyo relativo documentado. Se adopta el cero de proceso a 286,10 m solo para visualización; la equivalencia absoluta no está confirmada. No se añade un espesor de montaje sin cota del fabricante."} | ["La masa de 5 750 kg por unidad es el reparto uniforme de 23 000 kg del conjunto; confirmar el reparto real de cargas. Barandillas y sombreretes no se detallan.","El detalle de abril presenta una célula de 5,85 × 2,20 m; el contorno de agosto es de 5,85 × 2,14 m. Se usa el contorno de agosto. El ventilador se traslada al nuevo centro sin alterar su diámetro ni sus palas.","Las cotas intermedias 3,20 / 3,40 / 3,52 / 3,56 m no aparecen acotadas en el fabricante.","Espesor de palas de 0,04 m y altura del aro de 0,30 m: hipótesis de visualización.","La sección y altura reales de la estructura y de los paneles permanecen sin confirmar.","Los 25 pilares DZ9 terminan en +2,000; los cinco muros transversales terminan en +1,000. La instalación se asocia a los pilares superiores. El plano conserva -2,200 frente al fondo -2,000 de la sección.","El cero absoluto de la revisión no está definido; 286,10 m sigue siendo una hipótesis de coordinación.","Se alinea el punto inferior del conjunto del equipo, incluidos los pies ya representados, con la superficie de apoyo terminada; no se añade un espesor de calzos, placa o grout del fabricante no documentado."] | {"revision":"Detalle en planta de 2026-04-30 coordinado de forma preliminar con envolventes y alturas de 2026-08-25","status":"provisional","verticalRule":"Altura total documentada: 3,70 m. Distribución conceptual: cuerpo 0–3,20 m; plataforma superior 3,20–3,40 m; aro del ventilador 3,40–3,70 m; palas 3,52–3,56 m.","partCount":12,"source":{"documentId":"EQ-IMPLANTACION-20260430","title":"Plano del fabricante: implantación de equipos","sheet":"LHD2609-GD01000 · espacio modelo","date":"2026-04-30"},"heightSource":{"documentId":"EQ-CARGAS-20260825","title":"Plano del fabricante: cargas de equipos","sheet":"Espacio modelo","date":"2026-08-25"},"unconfirmedDimensions":["Las cotas intermedias 3,20 / 3,40 / 3,52 / 3,56 m no aparecen acotadas en el fabricante.","Espesor de palas de 0,04 m y altura del aro de 0,30 m: hipótesis de visualización.","La sección y altura reales de la estructura y de los paneles permanecen sin confirmar."],"quantityUse":"Magnitudes de la geometría representada; no son cantidades de material, obra, compra, capacidad útil ni fabricación. En geometrías compuestas se suman superficies y volúmenes de partes y pueden existir solapes no depurados.","partsAreBOM":false} | equipment_component | {"min":[36.44488,46.344292,3.1],"max":[42.53184,49.261142,6.8]} | {"boundingBoxM":{"min":[36.44488,46.344292,3.1],"max":[42.53184,49.261142,6.8]},"extentsM":[6.086960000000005,2.9168499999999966,3.6999999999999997],"meshSurfaceM2":106.9519119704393,"meshVolumeM3":42.21444876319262,"closedSolid":true,"windingConsistent":true,"basis":"Submalla exacta de los triángulos del modelo IFC coordinado; separación de componentes sin transformación ni retesselación."} | ["Las cotas intermedias 3,20 / 3,40 / 3,52 / 3,56 m no aparecen acotadas en el fabricante.","Espesor de palas de 0,04 m y altura del aro de 0,30 m: hipótesis de visualización.","La sección y altura reales de la estructura y de los paneles permanecen sin confirmar.","La separación gráfica no aporta cotas de fabricación ni identifica piezas internas no documentadas.","Los materiales y acabados permanecen provisionales; las fotografías públicas solo orientan la apariencia."] | {"id":"WT3001B--lateral-mount-1","sourcePartId":"WT3001B--lateral-mount-1","name":"Montaje lateral indicado en planta","role":"equipment_component","classificationStatus":"provisional","classificationBasis":"Rol del subvolumen gráfico según el activo de detalle; identidad de fabricación no confirmada.","parentEquipmentId":"WT3001B","parentEquipmentGuid":"3QfAgBB2zPsvSc6AB8$nne","isAssemblyIdentityCarrier":false,"sourceFaceRange":[2960,2972],"sourceCurrentFaceIndices":[2960,2961,2962,2963,2964,2965,2966,2967,2968,2969,2970,2971],"sourceMeshSha256":"7b60c904c9d84d22fded9be34af09a09a9c198ec8e75e61902634d5e4064c761","sourceVertexIndices":[1496,1497,1498,1499,1500,1501,1502,1503],"separationMethod":"Partición exacta de triángulos existentes; coordenadas y orientación de caras conservadas.","quantityUse":"Magnitudes geométricas del subvolumen; no son cantidades netas de material, fabricación, suministro o capacidad."} | {"id":"WT3001B","name":"Torre de refrigeración WT3001B","relationship":"decomposed_component","parentShapeMeaning":"La forma del objeto que conserva el ID del equipo es únicamente su componente principal; el conjunto completo requiere sus hijos."} | {"kind":"through_parent","parentEquipmentId":"WT3001B","directAnchorageVerified":false,"note":"La relación del conjunto con cimentaciones se conserva en el objeto que mantiene el ID del equipo; no se atribuye fijación directa a cada subcomponente."} | Documento de implantación y apoyo del conjunto padre; no acredita fijación individual de este componente. | WT3001B--lateral-mount-1 | Montaje lateral indicado en planta | Equipos | unknown | equipment_dark_frame | {"documentId":"EQ-IMPLANTACION-20260430","title":"Plano del fabricante: implantación de equipos","sheet":"LHD2609-GD01000 · espacio modelo","date":"2026-04-30","componentSourceHandles":["7080E"]} | Submalla de triángulos existentes; no hay nueva posición ni nuevas caras. | Cotas globales del conjunto conservadas aparte; las dimensiones de esta ficha son de la submalla. | Coordinación del conjunto padre; anclaje directo individual no acreditado. | Superficie y volumen geométricos brutos; no constituyen cantidades netas de obra, material o fabricación. | Plano general y dimensiones globales de WT3001B; no se asignan esas dimensiones globales a este componente. | ["7080E"] | 1 | no | Submalla exacta; interpretación funcional y cotas parciales provisionales.
Torre de refrigeración WT3001B · Montaje lateral indicado en planta | Componente de equipo · cuerpo o accesorio | Plano del fabricante: implantación de equipos · referencia E7 | 0.352925 | 0.340109 | 0.18 | 291.5 | 291.68 | 0.4104 | 0.01701 | Apoyo relativo +2.000 m; cero absoluto provisional | Componente de equipo · cuerpo o accesorio | equipmentComponent | {"name":"No especificado","source":"Sin especificación de material en la documentación revisada","status":"unknown"} | {"documented":[{"label":"Referencia dimensional del conjunto","value":"Plano general y dimensiones globales de WT3001B; no se asignan esas dimensiones globales a este componente.","unit":"","source":"EQ-IMPLANTACION-20260430 · LHD2609-GD01000 · espacio modelo","status":"referencia_del_conjunto"}],"geometry":[{"label":"Extensión de la malla en X","value":0.35292499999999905,"unit":"m","source":"Geometría releída del IFC; datum absoluto de proceso provisional","status":"derivado"},{"label":"Extensión de la malla en Y","value":0.3401089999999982,"unit":"m","source":"Geometría releída del IFC; datum absoluto de proceso provisional","status":"derivado"},{"label":"Extensión de la malla en Z","value":0.17999999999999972,"unit":"m","source":"Geometría releída del IFC; datum absoluto de proceso provisional","status":"derivado"},{"label":"Cota inferior de visualización","value":291.5,"unit":"m","source":"Geometría releída del IFC; datum absoluto de proceso provisional","status":"derivado"},{"label":"Cota superior de visualización","value":291.68,"unit":"m","source":"Geometría releída del IFC; datum absoluto de proceso provisional","status":"derivado"}],"notes":["Las dimensiones del equipo completo se conservan en parentEquipmentDimensions.","Las extensiones en X/Y son de los ejes del modelo y no sustituyen cotas locales de fabricación.","No se infieren espesores de chapa, tolerancias ni dimensiones de piezas a partir de la partición."]} | {"documentId":"EQ-IMPLANTACION-20260430","title":"Plano del fabricante: implantación de equipos","sheet":"LHD2609-GD01000 · espacio modelo","date":"2026-04-30","componentSourceHandles":["7085E"]} | {"horizontalStatus":"derivado_del_conjunto","verticalStatus":"derivado_del_conjunto","coordinateSystem":"model_local_m","parentEquipmentId":"WT3001B","transformApplied":false,"note":"Coordenadas copiadas exactamente del equipo coordinado; no se ha movido, girado, elevado ni reescalado este componente.","foundationRelationship":"El apoyo y las cotas de instalación se documentan para el conjunto padre. Esta submalla no acredita un anclaje directo.","meshMinimumAbsoluteElevationM":291.5,"assemblyPlacementField":"parentEquipmentPositioning"} | ["Componente separado de una reconstrucción documental del conjunto. Las alturas y detalles parciales conservan las limitaciones del fabricante registradas en parentEquipmentIssues.","Esta representación exterior no crea una chapa hueca ni añade componentes internos no documentados.","La pertenencia al conjunto no demuestra apoyo o anclaje directo a la cimentación."] | {"source":{"documentId":"EQ-IMPLANTACION-20260430","title":"Plano del fabricante: implantación de equipos","sheet":"LHD2609-GD01000 · espacio modelo","date":"2026-04-30","componentSourceHandles":["7085E"]},"sourcePartId":"WT3001B--lateral-mount-2","sourceHandles":["7085E"],"partCount":1,"partsAreBOM":false,"status":"Submalla exacta; interpretación funcional y cotas parciales provisionales."} | {"boundingBoxM":{"min":[41.529536,47.32777,6.5],"max":[41.882461,47.667879,6.68]},"extentsM":[0.352925,0.340109,0.18],"meshSurfaceM2":0.4104,"meshVolumeM3":0.01701,"closedSolid":true,"basis":"Geometría de coordinación. Los volúmenes de referencia y subcomponentes no son cantidades de material ni componentes de fabricación certificados."} | {"documentId":"LHD2609-JG00100-20260904","title":"Cimentaciones y pedestales de equipos · revisión recibida 04/09/2026","date":"2026-09-04","sheet":"9 / 9-9 / 9A-9A","sourceHandles":["2483D","24841","24772"]} | equipment | {"id":"equipment","name":"Equipos"} | {"profileId":"equipment_dark_frame","name":"Bastidor metálico · gris oscuro provisional","materialName":"No especificado","physicalMaterialStatus":"unknown","physicalMaterialSource":"Sin especificación de material en la documentación revisada","appearanceStatus":"provisional","appearanceBasis":"Referencia visual de fotografías públicas de Jinhong Gas / fabricante. Apariencia provisional para coordinación; fotografías oficiales pueden orientar el color, pero no acreditan el material, el acabado ni el equipo concreto.","appearanceReferences":["jinhong-official-asu"],"note":"El perfil visual no confirma material, grado ni acabado del componente."} | {"status":"componente_independiente","note":"Objeto independiente seleccionable. Las caras se asignan una sola vez entre todos los componentes del conjunto.","parentEquipmentId":"WT3001B","isAssemblyIdentityCarrier":false} | {"elementId":"WT3001B--lateral-mount-2","ifcGuid":"2hv4PMxUbKw8UPFwPPQJir","ifcClass":"IfcBuildingElementProxy","buildingId":"process_plant","buildingName":"Planta de proceso","sourceDocumentId":"EQ-IMPLANTACION-20260430","sourceRepresentationKind":"equipmentComponent"} | {"layerId":"equipment","layerName":"Equipos","role":"Componente de equipo · cuerpo o accesorio","basis":"Clasificación por función del elemento; no modifica las especificaciones documentales."} | {"profileId":"equipment_dark_frame","name":"Bastidor metálico · gris oscuro provisional","status":"provisional","basis":"Referencia visual de fotografías públicas de Jinhong Gas / fabricante. Apariencia provisional para coordinación; fotografías oficiales pueden orientar el color, pero no acreditan el material, el acabado ni el equipo concreto.","physicalMaterialUnchanged":true} | Equipos | No especificado | Equipos | Bastidor metálico · gris oscuro provisional | provisional | WT3001B--lateral-mount-2 | ["Componente separado de una reconstrucción documental del conjunto. Las alturas y detalles parciales conservan las limitaciones del fabricante registradas en parentEquipmentIssues.","Esta representación exterior no crea una chapa hueca ni añade componentes internos no documentados.","La pertenencia al conjunto no demuestra apoyo o anclaje directo a la cimentación."] | Geometría de coordinación. Los volúmenes de referencia y subcomponentes no son cantidades de material ni componentes de fabricación certificados. | Sin especificación de material en la documentación revisada | {"documentId":"EQ-IMPLANTACION-20260430","title":"Plano del fabricante: implantación de equipos","sheet":"LHD2609-GD01000 · espacio modelo","date":"2026-04-30","componentSourceHandles":["7085E"]} | yes | equipment_dark_frame | [0.290196,0.329412,0.34902] | 0.62 | 0.5 | Referencia visual de fotografías públicas de Jinhong Gas / fabricante. Apariencia provisional para coordinación; fotografías oficiales pueden orientar el color, pero no acreditan el material, el acabado ni el equipo concreto. | La apariencia no certifica el material físico ni el acabado de fabricación. | BIM · Equipos | WT3001B | Torre de refrigeración WT3001B | IfcCoolingTower | {"documented":[{"label":"Dimensión X local del contorno CAD","value":5.85,"unit":"m","source":"EQ-CARGAS-20260825 · contorno CAD · handles 524","status":"derivado"},{"label":"Dimensión Y local del contorno CAD","value":2.14,"unit":"m","source":"EQ-CARGAS-20260825 · contorno CAD · handles 524","status":"derivado"},{"label":"Altura acotada","value":3.7,"unit":"m","source":"EQ-CARGAS-20260825 · handle 2659","status":"documentado"},{"label":"Cota relativa de la superficie de apoyo","value":2.0,"unit":"m","source":"LHD2609-JG00100-20260904 · sección 9 / 9-9 / 9A-9A · 2483D, 24841, 24772","status":"documentado"}],"geometry":[{"label":"Extensión de la malla en X","value":6.086960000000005,"unit":"m","source":"Geometría releída del IFC; datum absoluto de proceso provisional","status":"derivado"},{"label":"Extensión de la malla en Y","value":2.9168499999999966,"unit":"m","source":"Geometría releída del IFC; datum absoluto de proceso provisional","status":"derivado"},{"label":"Extensión de la malla en Z","value":3.6999999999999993,"unit":"m","source":"Geometría releída del IFC; datum absoluto de proceso provisional","status":"derivado"},{"label":"Cota inferior de visualización","value":288.1,"unit":"m","source":"Geometría releída del IFC; datum absoluto de proceso provisional","status":"derivado"},{"label":"Cota superior de visualización","value":291.8,"unit":"m","source":"Geometría releída del IFC; datum absoluto de proceso provisional","status":"derivado"}],"notes":["Las extensiones de la malla se miden en los ejes del proyecto tras el giro de implantación; no sustituyen las dimensiones locales del fabricante.","La envolvente, su volumen y los espesores de visualización no son volúmenes de material ni cantidades de compra, construcción o fabricación.","Las dimensiones documentadas distinguen cotas explícitas y medidas extraídas de contornos CAD; las dimensiones geométricas describen únicamente la malla publicada.","Las extensiones de la malla refinada y las dimensiones documentadas del contorno o bastidor tienen distinto alcance; las cotas parciales del detalle son provisionales."]} | {"Estado de la planta":"Derivado del CAD y del giro de implantación","Nivel relativo del apoyo (m)":2.0,"Estado del nivel relativo":"Documentado en el plano de cimentaciones","Cero absoluto de visualización (m)":286.1,"Estado del cero absoluto":"Provisional","Cota del apoyo de visualización (m)":288.1,"Desplazamiento aplicado a la malla (m)":2.0000000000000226,"Criterio":"Nivel de apoyo relativo documentado. Se adopta el cero de proceso a 286,10 m solo para visualización; la equivalencia absoluta no está confirmada. No se añade un espesor de montaje sin cota del fabricante."} | ["La masa de 5 750 kg por unidad es el reparto uniforme de 23 000 kg del conjunto; confirmar el reparto real de cargas. Barandillas y sombreretes no se detallan.","El detalle de abril presenta una célula de 5,85 × 2,20 m; el contorno de agosto es de 5,85 × 2,14 m. Se usa el contorno de agosto. El ventilador se traslada al nuevo centro sin alterar su diámetro ni sus palas.","Las cotas intermedias 3,20 / 3,40 / 3,52 / 3,56 m no aparecen acotadas en el fabricante.","Espesor de palas de 0,04 m y altura del aro de 0,30 m: hipótesis de visualización.","La sección y altura reales de la estructura y de los paneles permanecen sin confirmar.","Los 25 pilares DZ9 terminan en +2,000; los cinco muros transversales terminan en +1,000. La instalación se asocia a los pilares superiores. El plano conserva -2,200 frente al fondo -2,000 de la sección.","El cero absoluto de la revisión no está definido; 286,10 m sigue siendo una hipótesis de coordinación.","Se alinea el punto inferior del conjunto del equipo, incluidos los pies ya representados, con la superficie de apoyo terminada; no se añade un espesor de calzos, placa o grout del fabricante no documentado."] | {"revision":"Detalle en planta de 2026-04-30 coordinado de forma preliminar con envolventes y alturas de 2026-08-25","status":"provisional","verticalRule":"Altura total documentada: 3,70 m. Distribución conceptual: cuerpo 0–3,20 m; plataforma superior 3,20–3,40 m; aro del ventilador 3,40–3,70 m; palas 3,52–3,56 m.","partCount":12,"source":{"documentId":"EQ-IMPLANTACION-20260430","title":"Plano del fabricante: implantación de equipos","sheet":"LHD2609-GD01000 · espacio modelo","date":"2026-04-30"},"heightSource":{"documentId":"EQ-CARGAS-20260825","title":"Plano del fabricante: cargas de equipos","sheet":"Espacio modelo","date":"2026-08-25"},"unconfirmedDimensions":["Las cotas intermedias 3,20 / 3,40 / 3,52 / 3,56 m no aparecen acotadas en el fabricante.","Espesor de palas de 0,04 m y altura del aro de 0,30 m: hipótesis de visualización.","La sección y altura reales de la estructura y de los paneles permanecen sin confirmar."],"quantityUse":"Magnitudes de la geometría representada; no son cantidades de material, obra, compra, capacidad útil ni fabricación. En geometrías compuestas se suman superficies y volúmenes de partes y pueden existir solapes no depurados.","partsAreBOM":false} | equipment_component | {"min":[36.44488,46.344292,3.1],"max":[42.53184,49.261142,6.8]} | {"boundingBoxM":{"min":[36.44488,46.344292,3.1],"max":[42.53184,49.261142,6.8]},"extentsM":[6.086960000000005,2.9168499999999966,3.6999999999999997],"meshSurfaceM2":106.9519119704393,"meshVolumeM3":42.21444876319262,"closedSolid":true,"windingConsistent":true,"basis":"Submalla exacta de los triángulos del modelo IFC coordinado; separación de componentes sin transformación ni retesselación."} | ["Las cotas intermedias 3,20 / 3,40 / 3,52 / 3,56 m no aparecen acotadas en el fabricante.","Espesor de palas de 0,04 m y altura del aro de 0,30 m: hipótesis de visualización.","La sección y altura reales de la estructura y de los paneles permanecen sin confirmar.","La separación gráfica no aporta cotas de fabricación ni identifica piezas internas no documentadas.","Los materiales y acabados permanecen provisionales; las fotografías públicas solo orientan la apariencia."] | {"id":"WT3001B--lateral-mount-2","sourcePartId":"WT3001B--lateral-mount-2","name":"Montaje lateral indicado en planta","role":"equipment_component","classificationStatus":"provisional","classificationBasis":"Rol del subvolumen gráfico según el activo de detalle; identidad de fabricación no confirmada.","parentEquipmentId":"WT3001B","parentEquipmentGuid":"3QfAgBB2zPsvSc6AB8$nne","isAssemblyIdentityCarrier":false,"sourceFaceRange":[2972,2984],"sourceCurrentFaceIndices":[2972,2973,2974,2975,2976,2977,2978,2979,2980,2981,2982,2983],"sourceMeshSha256":"7b60c904c9d84d22fded9be34af09a09a9c198ec8e75e61902634d5e4064c761","sourceVertexIndices":[1504,1505,1506,1507,1508,1509,1510,1511],"separationMethod":"Partición exacta de triángulos existentes; coordenadas y orientación de caras conservadas.","quantityUse":"Magnitudes geométricas del subvolumen; no son cantidades netas de material, fabricación, suministro o capacidad."} | {"id":"WT3001B","name":"Torre de refrigeración WT3001B","relationship":"decomposed_component","parentShapeMeaning":"La forma del objeto que conserva el ID del equipo es únicamente su componente principal; el conjunto completo requiere sus hijos."} | {"kind":"through_parent","parentEquipmentId":"WT3001B","directAnchorageVerified":false,"note":"La relación del conjunto con cimentaciones se conserva en el objeto que mantiene el ID del equipo; no se atribuye fijación directa a cada subcomponente."} | Documento de implantación y apoyo del conjunto padre; no acredita fijación individual de este componente. | WT3001B--lateral-mount-2 | Montaje lateral indicado en planta | Equipos | unknown | equipment_dark_frame | {"documentId":"EQ-IMPLANTACION-20260430","title":"Plano del fabricante: implantación de equipos","sheet":"LHD2609-GD01000 · espacio modelo","date":"2026-04-30","componentSourceHandles":["7085E"]} | Submalla de triángulos existentes; no hay nueva posición ni nuevas caras. | Cotas globales del conjunto conservadas aparte; las dimensiones de esta ficha son de la submalla. | Coordinación del conjunto padre; anclaje directo individual no acreditado. | Superficie y volumen geométricos brutos; no constituyen cantidades netas de obra, material o fabricación. | Plano general y dimensiones globales de WT3001B; no se asignan esas dimensiones globales a este componente. | ["7085E"] | 1 | no | Submalla exacta; interpretación funcional y cotas parciales provisionales.
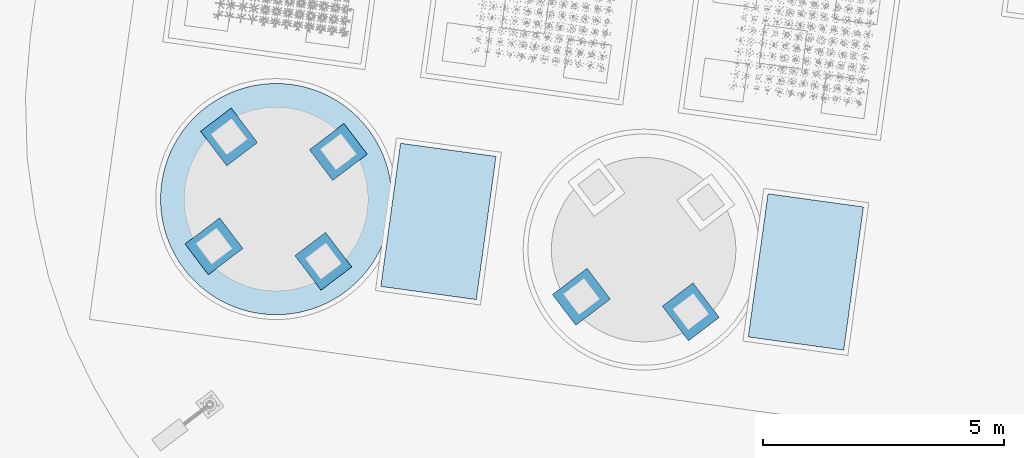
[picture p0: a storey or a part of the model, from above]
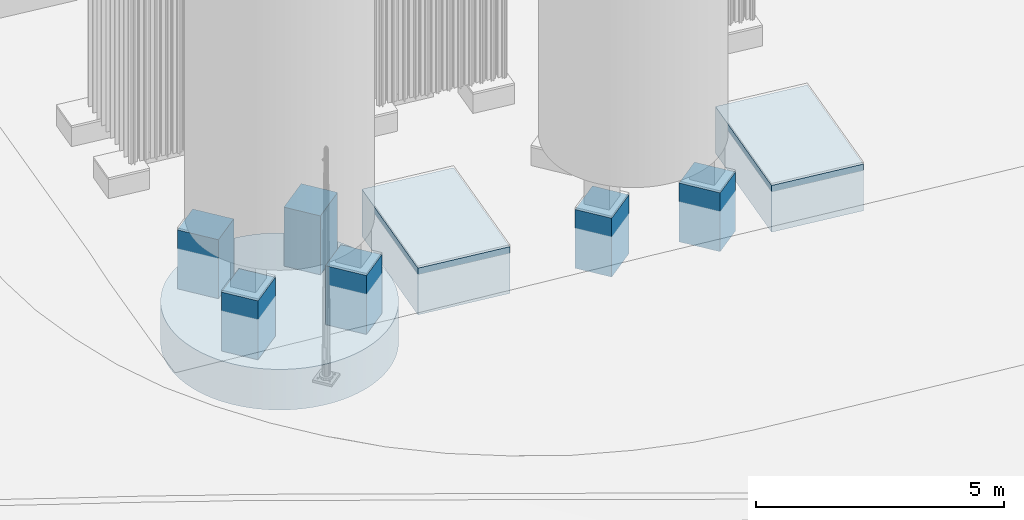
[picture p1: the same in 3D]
Properties of the parts of a building model (IFC4), part 18 of 134

# IfcBuildingElementProxy (140)
Name | Description | Document | Extensión de la malla en X (m) = ExtensionX (m) | Extensión de la malla en Y (m) = ExtensionY (m) | Extensión de la malla en Z (m) = ExtensionZ (m) | Cota inferior de visualización (m) | Cota superior de visualización (m) | SuperficieDeLaMalla (m2) | VolumenGeometrico (m3) | level | category = Categoria = Funcion | representationKind | material | dimensions | JH_InformacionBIM, source = DocumentoFuente | positioning = PosicionYEstado | issues | detailGeometry | geometryMetrics | installationSource | layerId = IdentificadorCapa | visualLayer | materialAppearance | componentSeparation | visualizationIdentity | classification | appearance | Disciplina | Material | Capa BIM = NombreCapa | Acabado de visualización = Acabado | Estado del acabado = Estado | Identificador | JH_Trazabilidad, IncidenciasPendientes | UsoDeLasMagnitudes | JH_EvidenciaDeMaterial, source | JH_DetalleGeometrico, source | VisibilidadInicial | Perfil | ColorRGB | Rugosidad | Metallicidad | Referencia | Nota | Group | parentEquipmentId = Identificador del equipo padre | parentEquipmentName = Equipo padre | parentEquipmentIfcClass | parentEquipmentDimensions | parentEquipmentPositioning | parentEquipmentIssues | parentEquipmentDetail | componentRole = Rol del componente | assemblyBBox | assemblyGeometryMetrics | manufacturerDetailsPending | component | assembly | foundationRelationship | installationSourceScope | Identificador del elemento = sourcePartId | Componente | Capa de visualización | Estado del material | Perfil visual del material | Fuente del componente | Criterio de partición | Criterio de las dimensiones | Relación con cimentaciones | Aplicabilidad de las mediciones | Referencia dimensional del conjunto | sourceHandles | partCount | partsAreBOM | status
Torre de refrigeración WT3001D · Pala de ventilador 1 · contorno CAD | Componente de equipo · cuerpo o accesorio | Plano del fabricante: implantación de equipos · referencia E7 | 0.338189 | 0.724372 | 0.04 | 291.62 | 291.66 | 0.189828 | 0.002482 | Apoyo relativo +2.000 m; cero absoluto provisional | Componente de equipo · cuerpo o accesorio | equipmentComponent | {"name":"No especificado","source":"Sin especificación de material en la documentación revisada","status":"unknown"} | {"documented":[{"label":"Referencia dimensional del conjunto","value":"Plano general y dimensiones globales de WT3001D; no se asignan esas dimensiones globales a este componente.","unit":"","source":"EQ-IMPLANTACION-20260430 · LHD2609-GD01000 · espacio modelo","status":"referencia_del_conjunto"}],"geometry":[{"label":"Extensión de la malla en X","value":0.33818899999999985,"unit":"m","source":"Geometría releída del IFC; datum absoluto de proceso provisional","status":"derivado"},{"label":"Extensión de la malla en Y","value":0.7243720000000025,"unit":"m","source":"Geometría releída del IFC; datum absoluto de proceso provisional","status":"derivado"},{"label":"Extensión de la malla en Z","value":0.040000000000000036,"unit":"m","source":"Geometría releída del IFC; datum absoluto de proceso provisional","status":"derivado"},{"label":"Cota inferior de visualización","value":291.62,"unit":"m","source":"Geometría releída del IFC; datum absoluto de proceso provisional","status":"derivado"},{"label":"Cota superior de visualización","value":291.66,"unit":"m","source":"Geometría releída del IFC; datum absoluto de proceso provisional","status":"derivado"}],"notes":["Las dimensiones del equipo completo se conservan en parentEquipmentDimensions.","Las extensiones en X/Y son de los ejes del modelo y no sustituyen cotas locales de fabricación.","No se infieren espesores de chapa, tolerancias ni dimensiones de piezas a partir de la partición."]} | {"documentId":"EQ-IMPLANTACION-20260430","title":"Plano del fabricante: implantación de equipos","sheet":"LHD2609-GD01000 · espacio modelo","date":"2026-04-30","componentSourceHandles":["70928"]} | {"horizontalStatus":"derivado_del_conjunto","verticalStatus":"derivado_del_conjunto","coordinateSystem":"model_local_m","parentEquipmentId":"WT3001D","transformApplied":false,"note":"Coordenadas copiadas exactamente del equipo coordinado; no se ha movido, girado, elevado ni reescalado este componente.","foundationRelationship":"El apoyo y las cotas de instalación se documentan para el conjunto padre. Esta submalla no acredita un anclaje directo.","meshMinimumAbsoluteElevationM":291.62,"assemblyPlacementField":"parentEquipmentPositioning"} | ["Componente separado de una reconstrucción documental del conjunto. Las alturas y detalles parciales conservan las limitaciones del fabricante registradas en parentEquipmentIssues.","Esta representación exterior no crea una chapa hueca ni añade componentes internos no documentados.","La pertenencia al conjunto no demuestra apoyo o anclaje directo a la cimentación."] | {"source":{"documentId":"EQ-IMPLANTACION-20260430","title":"Plano del fabricante: implantación de equipos","sheet":"LHD2609-GD01000 · espacio modelo","date":"2026-04-30","componentSourceHandles":["70928"]},"sourcePartId":"WT3001D--blade-01","sourceHandles":["70928"],"partCount":1,"partsAreBOM":false,"status":"Submalla exacta; interpretación funcional y cotas parciales provisionales."} | {"boundingBoxM":{"min":[38.531654,43.669602,6.62],"max":[38.869843,44.393974,6.66]},"extentsM":[0.338189,0.724372,0.04],"meshSurfaceM2":0.189828,"meshVolumeM3":0.002482,"closedSolid":true,"basis":"Geometría de coordinación. Los volúmenes de referencia y subcomponentes no son cantidades de material ni componentes de fabricación certificados."} | {"documentId":"LHD2609-JG00100-20260904","title":"Cimentaciones y pedestales de equipos · revisión recibida 04/09/2026","date":"2026-09-04","sheet":"9 / 9-9 / 9A-9A","sourceHandles":["2483D","24841","24772"]} | equipment | {"id":"equipment","name":"Equipos"} | {"profileId":"equipment_silver","name":"Intercambiador · metal gris provisional","materialName":"No especificado","physicalMaterialStatus":"unknown","physicalMaterialSource":"Sin especificación de material en la documentación revisada","appearanceStatus":"provisional","appearanceBasis":"Referencia visual de fotografías públicas de Jinhong Gas / fabricante. Apariencia provisional para coordinación; fotografías oficiales pueden orientar el color, pero no acreditan el material, el acabado ni el equipo concreto.","appearanceReferences":["jinhong-official-asu"],"note":"El perfil visual no confirma material, grado ni acabado del componente."} | {"status":"componente_independiente","note":"Objeto independiente seleccionable. Las caras se asignan una sola vez entre todos los componentes del conjunto.","parentEquipmentId":"WT3001D","isAssemblyIdentityCarrier":false} | {"elementId":"WT3001D--blade-01","ifcGuid":"3Kxg7GSNTNLgYXIaCiUo98","ifcClass":"IfcBuildingElementProxy","buildingId":"process_plant","buildingName":"Planta de proceso","sourceDocumentId":"EQ-IMPLANTACION-20260430","sourceRepresentationKind":"equipmentComponent"} | {"layerId":"equipment","layerName":"Equipos","role":"Componente de equipo · cuerpo o accesorio","basis":"Clasificación por función del elemento; no modifica las especificaciones documentales."} | {"profileId":"equipment_silver","name":"Intercambiador · metal gris provisional","status":"provisional","basis":"Referencia visual de fotografías públicas de Jinhong Gas / fabricante. Apariencia provisional para coordinación; fotografías oficiales pueden orientar el color, pero no acreditan el material, el acabado ni el equipo concreto.","physicalMaterialUnchanged":true} | Equipos | No especificado | Equipos | Intercambiador · metal gris provisional | provisional | WT3001D--blade-01 | ["Componente separado de una reconstrucción documental del conjunto. Las alturas y detalles parciales conservan las limitaciones del fabricante registradas en parentEquipmentIssues.","Esta representación exterior no crea una chapa hueca ni añade componentes internos no documentados.","La pertenencia al conjunto no demuestra apoyo o anclaje directo a la cimentación."] | Geometría de coordinación. Los volúmenes de referencia y subcomponentes no son cantidades de material ni componentes de fabricación certificados. | Sin especificación de material en la documentación revisada | {"documentId":"EQ-IMPLANTACION-20260430","title":"Plano del fabricante: implantación de equipos","sheet":"LHD2609-GD01000 · espacio modelo","date":"2026-04-30","componentSourceHandles":["70928"]} | yes | equipment_silver | [0.68,0.72,0.75] | 0.38 | 0.7 | Referencia visual de fotografías públicas de Jinhong Gas / fabricante. Apariencia provisional para coordinación; fotografías oficiales pueden orientar el color, pero no acreditan el material, el acabado ni el equipo concreto. | La apariencia no certifica el material físico ni el acabado de fabricación. | BIM · Equipos | WT3001D | Torre de refrigeración WT3001D | IfcCoolingTower | {"documented":[{"label":"Dimensión X local del contorno CAD","value":5.85,"unit":"m","source":"EQ-CARGAS-20260825 · contorno CAD · handles 526","status":"derivado"},{"label":"Dimensión Y local del contorno CAD","value":2.14,"unit":"m","source":"EQ-CARGAS-20260825 · contorno CAD · handles 526","status":"derivado"},{"label":"Altura acotada","value":3.7,"unit":"m","source":"EQ-CARGAS-20260825 · handle 2659","status":"documentado"},{"label":"Cota relativa de la superficie de apoyo","value":2.0,"unit":"m","source":"LHD2609-JG00100-20260904 · sección 9 / 9-9 / 9A-9A · 2483D, 24841, 24772","status":"documentado"}],"geometry":[{"label":"Extensión de la malla en X","value":6.086959,"unit":"m","source":"Geometría releída del IFC; datum absoluto de proceso provisional","status":"derivado"},{"label":"Extensión de la malla en Y","value":2.9168500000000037,"unit":"m","source":"Geometría releída del IFC; datum absoluto de proceso provisional","status":"derivado"},{"label":"Extensión de la malla en Z","value":3.6999999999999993,"unit":"m","source":"Geometría releída del IFC; datum absoluto de proceso provisional","status":"derivado"},{"label":"Cota inferior de visualización","value":288.1,"unit":"m","source":"Geometría releída del IFC; datum absoluto de proceso provisional","status":"derivado"},{"label":"Cota superior de visualización","value":291.8,"unit":"m","source":"Geometría releída del IFC; datum absoluto de proceso provisional","status":"derivado"}],"notes":["Las extensiones de la malla se miden en los ejes del proyecto tras el giro de implantación; no sustituyen las dimensiones locales del fabricante.","La envolvente, su volumen y los espesores de visualización no son volúmenes de material ni cantidades de compra, construcción o fabricación.","Las dimensiones documentadas distinguen cotas explícitas y medidas extraídas de contornos CAD; las dimensiones geométricas describen únicamente la malla publicada.","Las extensiones de la malla refinada y las dimensiones documentadas del contorno o bastidor tienen distinto alcance; las cotas parciales del detalle son provisionales."]} | {"Estado de la planta":"Derivado del CAD y del giro de implantación","Nivel relativo del apoyo (m)":2.0,"Estado del nivel relativo":"Documentado en el plano de cimentaciones","Cero absoluto de visualización (m)":286.1,"Estado del cero absoluto":"Provisional","Cota del apoyo de visualización (m)":288.1,"Desplazamiento aplicado a la malla (m)":2.0000000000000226,"Criterio":"Nivel de apoyo relativo documentado. Se adopta el cero de proceso a 286,10 m solo para visualización; la equivalencia absoluta no está confirmada. No se añade un espesor de montaje sin cota del fabricante."} | ["La masa de 5 750 kg por unidad es el reparto uniforme de 23 000 kg del conjunto; confirmar el reparto real de cargas. Barandillas y sombreretes no se detallan.","El detalle de abril presenta una célula de 5,85 × 2,20 m; el contorno de agosto es de 5,85 × 2,14 m. Se usa el contorno de agosto. El ventilador se traslada al nuevo centro sin alterar su diámetro ni sus palas.","Las cotas intermedias 3,20 / 3,40 / 3,52 / 3,56 m no aparecen acotadas en el fabricante.","Espesor de palas de 0,04 m y altura del aro de 0,30 m: hipótesis de visualización.","La sección y altura reales de la estructura y de los paneles permanecen sin confirmar.","Los 25 pilares DZ9 terminan en +2,000; los cinco muros transversales terminan en +1,000. La instalación se asocia a los pilares superiores. El plano conserva -2,200 frente al fondo -2,000 de la sección.","El cero absoluto de la revisión no está definido; 286,10 m sigue siendo una hipótesis de coordinación.","Se alinea el punto inferior del conjunto del equipo, incluidos los pies ya representados, con la superficie de apoyo terminada; no se añade un espesor de calzos, placa o grout del fabricante no documentado."] | {"revision":"Detalle en planta de 2026-04-30 coordinado de forma preliminar con envolventes y alturas de 2026-08-25","status":"provisional","verticalRule":"Altura total documentada: 3,70 m. Distribución conceptual: cuerpo 0–3,20 m; plataforma superior 3,20–3,40 m; aro del ventilador 3,40–3,70 m; palas 3,52–3,56 m.","partCount":12,"source":{"documentId":"EQ-IMPLANTACION-20260430","title":"Plano del fabricante: implantación de equipos","sheet":"LHD2609-GD01000 · espacio modelo","date":"2026-04-30"},"heightSource":{"documentId":"EQ-CARGAS-20260825","title":"Plano del fabricante: cargas de equipos","sheet":"Espacio modelo","date":"2026-08-25"},"unconfirmedDimensions":["Las cotas intermedias 3,20 / 3,40 / 3,52 / 3,56 m no aparecen acotadas en el fabricante.","Espesor de palas de 0,04 m y altura del aro de 0,30 m: hipótesis de visualización.","La sección y altura reales de la estructura y de los paneles permanecen sin confirmar."],"quantityUse":"Magnitudes de la geometría representada; no son cantidades de material, obra, compra, capacidad útil ni fabricación. En geometrías compuestas se suman superficies y volúmenes de partes y pueden existir solapes no depurados.","partsAreBOM":false} | equipment_component | {"min":[35.861928,42.104178,3.1],"max":[41.948887,45.021028,6.8]} | {"boundingBoxM":{"min":[35.861928,42.104178,3.1],"max":[41.948887,45.021028,6.8]},"extentsM":[6.086959,2.9168500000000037,3.6999999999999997],"meshSurfaceM2":106.95190117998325,"meshVolumeM3":42.214443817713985,"closedSolid":true,"windingConsistent":true,"basis":"Submalla exacta de los triángulos del modelo IFC coordinado; separación de componentes sin transformación ni retesselación."} | ["Las cotas intermedias 3,20 / 3,40 / 3,52 / 3,56 m no aparecen acotadas en el fabricante.","Espesor de palas de 0,04 m y altura del aro de 0,30 m: hipótesis de visualización.","La sección y altura reales de la estructura y de los paneles permanecen sin confirmar.","La separación gráfica no aporta cotas de fabricación ni identifica piezas internas no documentadas.","Los materiales y acabados permanecen provisionales; las fotografías públicas solo orientan la apariencia."] | {"id":"WT3001D--blade-01","sourcePartId":"WT3001D--blade-01","name":"Pala de ventilador 1 · contorno CAD","role":"equipment_component","classificationStatus":"provisional","classificationBasis":"Rol del subvolumen gráfico según el activo de detalle; identidad de fabricación no confirmada.","parentEquipmentId":"WT3001D","parentEquipmentGuid":"2AZFhKNMnMognqXDVjGcnW","isAssemblyIdentityCarrier":false,"sourceFaceRange":[2332,2352],"sourceCurrentFaceIndices":[2332,2333,2334,2335,2336,2337,2338,2339,2340,2341,2342,2343,2344,2345,2346,2347,2348,2349,2350,2351],"sourceMeshSha256":"7b60c904c9d84d22fded9be34af09a09a9c198ec8e75e61902634d5e4064c761","sourceVertexIndices":[1168,1169,1170,1171,1172,1173,1174,1175,1176,1177,1178,1179],"separationMethod":"Partición exacta de triángulos existentes; coordenadas y orientación de caras conservadas.","quantityUse":"Magnitudes geométricas del subvolumen; no son cantidades netas de material, fabricación, suministro o capacidad."} | {"id":"WT3001D","name":"Torre de refrigeración WT3001D","relationship":"decomposed_component","parentShapeMeaning":"La forma del objeto que conserva el ID del equipo es únicamente su componente principal; el conjunto completo requiere sus hijos."} | {"kind":"through_parent","parentEquipmentId":"WT3001D","directAnchorageVerified":false,"note":"La relación del conjunto con cimentaciones se conserva en el objeto que mantiene el ID del equipo; no se atribuye fijación directa a cada subcomponente."} | Documento de implantación y apoyo del conjunto padre; no acredita fijación individual de este componente. | WT3001D--blade-01 | Pala de ventilador 1 · contorno CAD | Equipos | unknown | equipment_silver | {"documentId":"EQ-IMPLANTACION-20260430","title":"Plano del fabricante: implantación de equipos","sheet":"LHD2609-GD01000 · espacio modelo","date":"2026-04-30","componentSourceHandles":["70928"]} | Submalla de triángulos existentes; no hay nueva posición ni nuevas caras. | Cotas globales del conjunto conservadas aparte; las dimensiones de esta ficha son de la submalla. | Coordinación del conjunto padre; anclaje directo individual no acreditado. | Superficie y volumen geométricos brutos; no constituyen cantidades netas de obra, material o fabricación. | Plano general y dimensiones globales de WT3001D; no se asignan esas dimensiones globales a este componente. | ["70928"] | 1 | no | Submalla exacta; interpretación funcional y cotas parciales provisionales.
Torre de refrigeración WT3001D · Pala de ventilador 2 · contorno CAD | Componente de equipo · cuerpo o accesorio | Plano del fabricante: implantación de equipos · referencia E7 | 0.338189 | 0.724373 | 0.04 | 291.62 | 291.66 | 0.189828 | 0.002482 | Apoyo relativo +2.000 m; cero absoluto provisional | Componente de equipo · cuerpo o accesorio | equipmentComponent | {"name":"No especificado","source":"Sin especificación de material en la documentación revisada","status":"unknown"} | {"documented":[{"label":"Referencia dimensional del conjunto","value":"Plano general y dimensiones globales de WT3001D; no se asignan esas dimensiones globales a este componente.","unit":"","source":"EQ-IMPLANTACION-20260430 · LHD2609-GD01000 · espacio modelo","status":"referencia_del_conjunto"}],"geometry":[{"label":"Extensión de la malla en X","value":0.33818899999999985,"unit":"m","source":"Geometría releída del IFC; datum absoluto de proceso provisional","status":"derivado"},{"label":"Extensión de la malla en Y","value":0.7243729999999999,"unit":"m","source":"Geometría releída del IFC; datum absoluto de proceso provisional","status":"derivado"},{"label":"Extensión de la malla en Z","value":0.040000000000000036,"unit":"m","source":"Geometría releída del IFC; datum absoluto de proceso provisional","status":"derivado"},{"label":"Cota inferior de visualización","value":291.62,"unit":"m","source":"Geometría releída del IFC; datum absoluto de proceso provisional","status":"derivado"},{"label":"Cota superior de visualización","value":291.66,"unit":"m","source":"Geometría releída del IFC; datum absoluto de proceso provisional","status":"derivado"}],"notes":["Las dimensiones del equipo completo se conservan en parentEquipmentDimensions.","Las extensiones en X/Y son de los ejes del modelo y no sustituyen cotas locales de fabricación.","No se infieren espesores de chapa, tolerancias ni dimensiones de piezas a partir de la partición."]} | {"documentId":"EQ-IMPLANTACION-20260430","title":"Plano del fabricante: implantación de equipos","sheet":"LHD2609-GD01000 · espacio modelo","date":"2026-04-30","componentSourceHandles":["7093F"]} | {"horizontalStatus":"derivado_del_conjunto","verticalStatus":"derivado_del_conjunto","coordinateSystem":"model_local_m","parentEquipmentId":"WT3001D","transformApplied":false,"note":"Coordenadas copiadas exactamente del equipo coordinado; no se ha movido, girado, elevado ni reescalado este componente.","foundationRelationship":"El apoyo y las cotas de instalación se documentan para el conjunto padre. Esta submalla no acredita un anclaje directo.","meshMinimumAbsoluteElevationM":291.62,"assemblyPlacementField":"parentEquipmentPositioning"} | ["Componente separado de una reconstrucción documental del conjunto. Las alturas y detalles parciales conservan las limitaciones del fabricante registradas en parentEquipmentIssues.","Esta representación exterior no crea una chapa hueca ni añade componentes internos no documentados.","La pertenencia al conjunto no demuestra apoyo o anclaje directo a la cimentación."] | {"source":{"documentId":"EQ-IMPLANTACION-20260430","title":"Plano del fabricante: implantación de equipos","sheet":"LHD2609-GD01000 · espacio modelo","date":"2026-04-30","componentSourceHandles":["7093F"]},"sourcePartId":"WT3001D--blade-02","sourceHandles":["7093F"],"partCount":1,"partsAreBOM":false,"status":"Submalla exacta; interpretación funcional y cotas parciales provisionales."} | {"boundingBoxM":{"min":[38.940971,42.731231,6.62],"max":[39.27916,43.455604,6.66]},"extentsM":[0.338189,0.724373,0.04],"meshSurfaceM2":0.189828,"meshVolumeM3":0.002482,"closedSolid":true,"basis":"Geometría de coordinación. Los volúmenes de referencia y subcomponentes no son cantidades de material ni componentes de fabricación certificados."} | {"documentId":"LHD2609-JG00100-20260904","title":"Cimentaciones y pedestales de equipos · revisión recibida 04/09/2026","date":"2026-09-04","sheet":"9 / 9-9 / 9A-9A","sourceHandles":["2483D","24841","24772"]} | equipment | {"id":"equipment","name":"Equipos"} | {"profileId":"equipment_silver","name":"Intercambiador · metal gris provisional","materialName":"No especificado","physicalMaterialStatus":"unknown","physicalMaterialSource":"Sin especificación de material en la documentación revisada","appearanceStatus":"provisional","appearanceBasis":"Referencia visual de fotografías públicas de Jinhong Gas / fabricante. Apariencia provisional para coordinación; fotografías oficiales pueden orientar el color, pero no acreditan el material, el acabado ni el equipo concreto.","appearanceReferences":["jinhong-official-asu"],"note":"El perfil visual no confirma material, grado ni acabado del componente."} | {"status":"componente_independiente","note":"Objeto independiente seleccionable. Las caras se asignan una sola vez entre todos los componentes del conjunto.","parentEquipmentId":"WT3001D","isAssemblyIdentityCarrier":false} | {"elementId":"WT3001D--blade-02","ifcGuid":"1Yove7CeDQkAv9X7GSo5R9","ifcClass":"IfcBuildingElementProxy","buildingId":"process_plant","buildingName":"Planta de proceso","sourceDocumentId":"EQ-IMPLANTACION-20260430","sourceRepresentationKind":"equipmentComponent"} | {"layerId":"equipment","layerName":"Equipos","role":"Componente de equipo · cuerpo o accesorio","basis":"Clasificación por función del elemento; no modifica las especificaciones documentales."} | {"profileId":"equipment_silver","name":"Intercambiador · metal gris provisional","status":"provisional","basis":"Referencia visual de fotografías públicas de Jinhong Gas / fabricante. Apariencia provisional para coordinación; fotografías oficiales pueden orientar el color, pero no acreditan el material, el acabado ni el equipo concreto.","physicalMaterialUnchanged":true} | Equipos | No especificado | Equipos | Intercambiador · metal gris provisional | provisional | WT3001D--blade-02 | ["Componente separado de una reconstrucción documental del conjunto. Las alturas y detalles parciales conservan las limitaciones del fabricante registradas en parentEquipmentIssues.","Esta representación exterior no crea una chapa hueca ni añade componentes internos no documentados.","La pertenencia al conjunto no demuestra apoyo o anclaje directo a la cimentación."] | Geometría de coordinación. Los volúmenes de referencia y subcomponentes no son cantidades de material ni componentes de fabricación certificados. | Sin especificación de material en la documentación revisada | {"documentId":"EQ-IMPLANTACION-20260430","title":"Plano del fabricante: implantación de equipos","sheet":"LHD2609-GD01000 · espacio modelo","date":"2026-04-30","componentSourceHandles":["7093F"]} | yes | equipment_silver | [0.68,0.72,0.75] | 0.38 | 0.7 | Referencia visual de fotografías públicas de Jinhong Gas / fabricante. Apariencia provisional para coordinación; fotografías oficiales pueden orientar el color, pero no acreditan el material, el acabado ni el equipo concreto. | La apariencia no certifica el material físico ni el acabado de fabricación. | BIM · Equipos | WT3001D | Torre de refrigeración WT3001D | IfcCoolingTower | {"documented":[{"label":"Dimensión X local del contorno CAD","value":5.85,"unit":"m","source":"EQ-CARGAS-20260825 · contorno CAD · handles 526","status":"derivado"},{"label":"Dimensión Y local del contorno CAD","value":2.14,"unit":"m","source":"EQ-CARGAS-20260825 · contorno CAD · handles 526","status":"derivado"},{"label":"Altura acotada","value":3.7,"unit":"m","source":"EQ-CARGAS-20260825 · handle 2659","status":"documentado"},{"label":"Cota relativa de la superficie de apoyo","value":2.0,"unit":"m","source":"LHD2609-JG00100-20260904 · sección 9 / 9-9 / 9A-9A · 2483D, 24841, 24772","status":"documentado"}],"geometry":[{"label":"Extensión de la malla en X","value":6.086959,"unit":"m","source":"Geometría releída del IFC; datum absoluto de proceso provisional","status":"derivado"},{"label":"Extensión de la malla en Y","value":2.9168500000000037,"unit":"m","source":"Geometría releída del IFC; datum absoluto de proceso provisional","status":"derivado"},{"label":"Extensión de la malla en Z","value":3.6999999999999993,"unit":"m","source":"Geometría releída del IFC; datum absoluto de proceso provisional","status":"derivado"},{"label":"Cota inferior de visualización","value":288.1,"unit":"m","source":"Geometría releída del IFC; datum absoluto de proceso provisional","status":"derivado"},{"label":"Cota superior de visualización","value":291.8,"unit":"m","source":"Geometría releída del IFC; datum absoluto de proceso provisional","status":"derivado"}],"notes":["Las extensiones de la malla se miden en los ejes del proyecto tras el giro de implantación; no sustituyen las dimensiones locales del fabricante.","La envolvente, su volumen y los espesores de visualización no son volúmenes de material ni cantidades de compra, construcción o fabricación.","Las dimensiones documentadas distinguen cotas explícitas y medidas extraídas de contornos CAD; las dimensiones geométricas describen únicamente la malla publicada.","Las extensiones de la malla refinada y las dimensiones documentadas del contorno o bastidor tienen distinto alcance; las cotas parciales del detalle son provisionales."]} | {"Estado de la planta":"Derivado del CAD y del giro de implantación","Nivel relativo del apoyo (m)":2.0,"Estado del nivel relativo":"Documentado en el plano de cimentaciones","Cero absoluto de visualización (m)":286.1,"Estado del cero absoluto":"Provisional","Cota del apoyo de visualización (m)":288.1,"Desplazamiento aplicado a la malla (m)":2.0000000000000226,"Criterio":"Nivel de apoyo relativo documentado. Se adopta el cero de proceso a 286,10 m solo para visualización; la equivalencia absoluta no está confirmada. No se añade un espesor de montaje sin cota del fabricante."} | ["La masa de 5 750 kg por unidad es el reparto uniforme de 23 000 kg del conjunto; confirmar el reparto real de cargas. Barandillas y sombreretes no se detallan.","El detalle de abril presenta una célula de 5,85 × 2,20 m; el contorno de agosto es de 5,85 × 2,14 m. Se usa el contorno de agosto. El ventilador se traslada al nuevo centro sin alterar su diámetro ni sus palas.","Las cotas intermedias 3,20 / 3,40 / 3,52 / 3,56 m no aparecen acotadas en el fabricante.","Espesor de palas de 0,04 m y altura del aro de 0,30 m: hipótesis de visualización.","La sección y altura reales de la estructura y de los paneles permanecen sin confirmar.","Los 25 pilares DZ9 terminan en +2,000; los cinco muros transversales terminan en +1,000. La instalación se asocia a los pilares superiores. El plano conserva -2,200 frente al fondo -2,000 de la sección.","El cero absoluto de la revisión no está definido; 286,10 m sigue siendo una hipótesis de coordinación.","Se alinea el punto inferior del conjunto del equipo, incluidos los pies ya representados, con la superficie de apoyo terminada; no se añade un espesor de calzos, placa o grout del fabricante no documentado."] | {"revision":"Detalle en planta de 2026-04-30 coordinado de forma preliminar con envolventes y alturas de 2026-08-25","status":"provisional","verticalRule":"Altura total documentada: 3,70 m. Distribución conceptual: cuerpo 0–3,20 m; plataforma superior 3,20–3,40 m; aro del ventilador 3,40–3,70 m; palas 3,52–3,56 m.","partCount":12,"source":{"documentId":"EQ-IMPLANTACION-20260430","title":"Plano del fabricante: implantación de equipos","sheet":"LHD2609-GD01000 · espacio modelo","date":"2026-04-30"},"heightSource":{"documentId":"EQ-CARGAS-20260825","title":"Plano del fabricante: cargas de equipos","sheet":"Espacio modelo","date":"2026-08-25"},"unconfirmedDimensions":["Las cotas intermedias 3,20 / 3,40 / 3,52 / 3,56 m no aparecen acotadas en el fabricante.","Espesor de palas de 0,04 m y altura del aro de 0,30 m: hipótesis de visualización.","La sección y altura reales de la estructura y de los paneles permanecen sin confirmar."],"quantityUse":"Magnitudes de la geometría representada; no son cantidades de material, obra, compra, capacidad útil ni fabricación. En geometrías compuestas se suman superficies y volúmenes de partes y pueden existir solapes no depurados.","partsAreBOM":false} | equipment_component | {"min":[35.861928,42.104178,3.1],"max":[41.948887,45.021028,6.8]} | {"boundingBoxM":{"min":[35.861928,42.104178,3.1],"max":[41.948887,45.021028,6.8]},"extentsM":[6.086959,2.9168500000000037,3.6999999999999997],"meshSurfaceM2":106.95190117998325,"meshVolumeM3":42.214443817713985,"closedSolid":true,"windingConsistent":true,"basis":"Submalla exacta de los triángulos del modelo IFC coordinado; separación de componentes sin transformación ni retesselación."} | ["Las cotas intermedias 3,20 / 3,40 / 3,52 / 3,56 m no aparecen acotadas en el fabricante.","Espesor de palas de 0,04 m y altura del aro de 0,30 m: hipótesis de visualización.","La sección y altura reales de la estructura y de los paneles permanecen sin confirmar.","La separación gráfica no aporta cotas de fabricación ni identifica piezas internas no documentadas.","Los materiales y acabados permanecen provisionales; las fotografías públicas solo orientan la apariencia."] | {"id":"WT3001D--blade-02","sourcePartId":"WT3001D--blade-02","name":"Pala de ventilador 2 · contorno CAD","role":"equipment_component","classificationStatus":"provisional","classificationBasis":"Rol del subvolumen gráfico según el activo de detalle; identidad de fabricación no confirmada.","parentEquipmentId":"WT3001D","parentEquipmentGuid":"2AZFhKNMnMognqXDVjGcnW","isAssemblyIdentityCarrier":false,"sourceFaceRange":[2352,2372],"sourceCurrentFaceIndices":[2352,2353,2354,2355,2356,2357,2358,2359,2360,2361,2362,2363,2364,2365,2366,2367,2368,2369,2370,2371],"sourceMeshSha256":"7b60c904c9d84d22fded9be34af09a09a9c198ec8e75e61902634d5e4064c761","sourceVertexIndices":[1180,1181,1182,1183,1184,1185,1186,1187,1188,1189,1190,1191],"separationMethod":"Partición exacta de triángulos existentes; coordenadas y orientación de caras conservadas.","quantityUse":"Magnitudes geométricas del subvolumen; no son cantidades netas de material, fabricación, suministro o capacidad."} | {"id":"WT3001D","name":"Torre de refrigeración WT3001D","relationship":"decomposed_component","parentShapeMeaning":"La forma del objeto que conserva el ID del equipo es únicamente su componente principal; el conjunto completo requiere sus hijos."} | {"kind":"through_parent","parentEquipmentId":"WT3001D","directAnchorageVerified":false,"note":"La relación del conjunto con cimentaciones se conserva en el objeto que mantiene el ID del equipo; no se atribuye fijación directa a cada subcomponente."} | Documento de implantación y apoyo del conjunto padre; no acredita fijación individual de este componente. | WT3001D--blade-02 | Pala de ventilador 2 · contorno CAD | Equipos | unknown | equipment_silver | {"documentId":"EQ-IMPLANTACION-20260430","title":"Plano del fabricante: implantación de equipos","sheet":"LHD2609-GD01000 · espacio modelo","date":"2026-04-30","componentSourceHandles":["7093F"]} | Submalla de triángulos existentes; no hay nueva posición ni nuevas caras. | Cotas globales del conjunto conservadas aparte; las dimensiones de esta ficha son de la submalla. | Coordinación del conjunto padre; anclaje directo individual no acreditado. | Superficie y volumen geométricos brutos; no constituyen cantidades netas de obra, material o fabricación. | Plano general y dimensiones globales de WT3001D; no se asignan esas dimensiones globales a este componente. | ["7093F"] | 1 | no | Submalla exacta; interpretación funcional y cotas parciales provisionales.
Torre de refrigeración WT3001D · Pala de ventilador 3 · contorno CAD | Componente de equipo · cuerpo o accesorio | Plano del fabricante: implantación de equipos · referencia E7 | 0.525639 | 0.627196 | 0.04 | 291.62 | 291.66 | 0.189829 | 0.002482 | Apoyo relativo +2.000 m; cero absoluto provisional | Componente de equipo · cuerpo o accesorio | equipmentComponent | {"name":"No especificado","source":"Sin especificación de material en la documentación revisada","status":"unknown"} | {"documented":[{"label":"Referencia dimensional del conjunto","value":"Plano general y dimensiones globales de WT3001D; no se asignan esas dimensiones globales a este componente.","unit":"","source":"EQ-IMPLANTACION-20260430 · LHD2609-GD01000 · espacio modelo","status":"referencia_del_conjunto"}],"geometry":[{"label":"Extensión de la malla en X","value":0.5256389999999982,"unit":"m","source":"Geometría releída del IFC; datum absoluto de proceso provisional","status":"derivado"},{"label":"Extensión de la malla en Y","value":0.6271959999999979,"unit":"m","source":"Geometría releída del IFC; datum absoluto de proceso provisional","status":"derivado"},{"label":"Extensión de la malla en Z","value":0.040000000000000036,"unit":"m","source":"Geometría releída del IFC; datum absoluto de proceso provisional","status":"derivado"},{"label":"Cota inferior de visualización","value":291.62,"unit":"m","source":"Geometría releída del IFC; datum absoluto de proceso provisional","status":"derivado"},{"label":"Cota superior de visualización","value":291.66,"unit":"m","source":"Geometría releída del IFC; datum absoluto de proceso provisional","status":"derivado"}],"notes":["Las dimensiones del equipo completo se conservan en parentEquipmentDimensions.","Las extensiones en X/Y son de los ejes del modelo y no sustituyen cotas locales de fabricación.","No se infieren espesores de chapa, tolerancias ni dimensiones de piezas a partir de la partición."]} | {"documentId":"EQ-IMPLANTACION-20260430","title":"Plano del fabricante: implantación de equipos","sheet":"LHD2609-GD01000 · espacio modelo","date":"2026-04-30","componentSourceHandles":["70956"]} | {"horizontalStatus":"derivado_del_conjunto","verticalStatus":"derivado_del_conjunto","coordinateSystem":"model_local_m","parentEquipmentId":"WT3001D","transformApplied":false,"note":"Coordenadas copiadas exactamente del equipo coordinado; no se ha movido, girado, elevado ni reescalado este componente.","foundationRelationship":"El apoyo y las cotas de instalación se documentan para el conjunto padre. Esta submalla no acredita un anclaje directo.","meshMinimumAbsoluteElevationM":291.62,"assemblyPlacementField":"parentEquipmentPositioning"} | ["Componente separado de una reconstrucción documental del conjunto. Las alturas y detalles parciales conservan las limitaciones del fabricante registradas en parentEquipmentIssues.","Esta representación exterior no crea una chapa hueca ni añade componentes internos no documentados.","La pertenencia al conjunto no demuestra apoyo o anclaje directo a la cimentación."] | {"source":{"documentId":"EQ-IMPLANTACION-20260430","title":"Plano del fabricante: implantación de equipos","sheet":"LHD2609-GD01000 · espacio modelo","date":"2026-04-30","componentSourceHandles":["70956"]},"sourcePartId":"WT3001D--blade-03","sourceHandles":["70956"],"partCount":1,"partsAreBOM":false,"status":"Submalla exacta; interpretación funcional y cotas parciales provisionales."} | {"boundingBoxM":{"min":[38.344259,42.835064,6.62],"max":[38.869898,43.46226,6.66]},"extentsM":[0.525639,0.627196,0.04],"meshSurfaceM2":0.189829,"meshVolumeM3":0.002482,"closedSolid":true,"basis":"Geometría de coordinación. Los volúmenes de referencia y subcomponentes no son cantidades de material ni componentes de fabricación certificados."} | {"documentId":"LHD2609-JG00100-20260904","title":"Cimentaciones y pedestales de equipos · revisión recibida 04/09/2026","date":"2026-09-04","sheet":"9 / 9-9 / 9A-9A","sourceHandles":["2483D","24841","24772"]} | equipment | {"id":"equipment","name":"Equipos"} | {"profileId":"equipment_silver","name":"Intercambiador · metal gris provisional","materialName":"No especificado","physicalMaterialStatus":"unknown","physicalMaterialSource":"Sin especificación de material en la documentación revisada","appearanceStatus":"provisional","appearanceBasis":"Referencia visual de fotografías públicas de Jinhong Gas / fabricante. Apariencia provisional para coordinación; fotografías oficiales pueden orientar el color, pero no acreditan el material, el acabado ni el equipo concreto.","appearanceReferences":["jinhong-official-asu"],"note":"El perfil visual no confirma material, grado ni acabado del componente."} | {"status":"componente_independiente","note":"Objeto independiente seleccionable. Las caras se asignan una sola vez entre todos los componentes del conjunto.","parentEquipmentId":"WT3001D","isAssemblyIdentityCarrier":false} | {"elementId":"WT3001D--blade-03","ifcGuid":"1t1CU6dhDJl9q3b4ngKIVW","ifcClass":"IfcBuildingElementProxy","buildingId":"process_plant","buildingName":"Planta de proceso","sourceDocumentId":"EQ-IMPLANTACION-20260430","sourceRepresentationKind":"equipmentComponent"} | {"layerId":"equipment","layerName":"Equipos","role":"Componente de equipo · cuerpo o accesorio","basis":"Clasificación por función del elemento; no modifica las especificaciones documentales."} | {"profileId":"equipment_silver","name":"Intercambiador · metal gris provisional","status":"provisional","basis":"Referencia visual de fotografías públicas de Jinhong Gas / fabricante. Apariencia provisional para coordinación; fotografías oficiales pueden orientar el color, pero no acreditan el material, el acabado ni el equipo concreto.","physicalMaterialUnchanged":true} | Equipos | No especificado | Equipos | Intercambiador · metal gris provisional | provisional | WT3001D--blade-03 | ["Componente separado de una reconstrucción documental del conjunto. Las alturas y detalles parciales conservan las limitaciones del fabricante registradas en parentEquipmentIssues.","Esta representación exterior no crea una chapa hueca ni añade componentes internos no documentados.","La pertenencia al conjunto no demuestra apoyo o anclaje directo a la cimentación."] | Geometría de coordinación. Los volúmenes de referencia y subcomponentes no son cantidades de material ni componentes de fabricación certificados. | Sin especificación de material en la documentación revisada | {"documentId":"EQ-IMPLANTACION-20260430","title":"Plano del fabricante: implantación de equipos","sheet":"LHD2609-GD01000 · espacio modelo","date":"2026-04-30","componentSourceHandles":["70956"]} | yes | equipment_silver | [0.68,0.72,0.75] | 0.38 | 0.7 | Referencia visual de fotografías públicas de Jinhong Gas / fabricante. Apariencia provisional para coordinación; fotografías oficiales pueden orientar el color, pero no acreditan el material, el acabado ni el equipo concreto. | La apariencia no certifica el material físico ni el acabado de fabricación. | BIM · Equipos | WT3001D | Torre de refrigeración WT3001D | IfcCoolingTower | {"documented":[{"label":"Dimensión X local del contorno CAD","value":5.85,"unit":"m","source":"EQ-CARGAS-20260825 · contorno CAD · handles 526","status":"derivado"},{"label":"Dimensión Y local del contorno CAD","value":2.14,"unit":"m","source":"EQ-CARGAS-20260825 · contorno CAD · handles 526","status":"derivado"},{"label":"Altura acotada","value":3.7,"unit":"m","source":"EQ-CARGAS-20260825 · handle 2659","status":"documentado"},{"label":"Cota relativa de la superficie de apoyo","value":2.0,"unit":"m","source":"LHD2609-JG00100-20260904 · sección 9 / 9-9 / 9A-9A · 2483D, 24841, 24772","status":"documentado"}],"geometry":[{"label":"Extensión de la malla en X","value":6.086959,"unit":"m","source":"Geometría releída del IFC; datum absoluto de proceso provisional","status":"derivado"},{"label":"Extensión de la malla en Y","value":2.9168500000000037,"unit":"m","source":"Geometría releída del IFC; datum absoluto de proceso provisional","status":"derivado"},{"label":"Extensión de la malla en Z","value":3.6999999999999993,"unit":"m","source":"Geometría releída del IFC; datum absoluto de proceso provisional","status":"derivado"},{"label":"Cota inferior de visualización","value":288.1,"unit":"m","source":"Geometría releída del IFC; datum absoluto de proceso provisional","status":"derivado"},{"label":"Cota superior de visualización","value":291.8,"unit":"m","source":"Geometría releída del IFC; datum absoluto de proceso provisional","status":"derivado"}],"notes":["Las extensiones de la malla se miden en los ejes del proyecto tras el giro de implantación; no sustituyen las dimensiones locales del fabricante.","La envolvente, su volumen y los espesores de visualización no son volúmenes de material ni cantidades de compra, construcción o fabricación.","Las dimensiones documentadas distinguen cotas explícitas y medidas extraídas de contornos CAD; las dimensiones geométricas describen únicamente la malla publicada.","Las extensiones de la malla refinada y las dimensiones documentadas del contorno o bastidor tienen distinto alcance; las cotas parciales del detalle son provisionales."]} | {"Estado de la planta":"Derivado del CAD y del giro de implantación","Nivel relativo del apoyo (m)":2.0,"Estado del nivel relativo":"Documentado en el plano de cimentaciones","Cero absoluto de visualización (m)":286.1,"Estado del cero absoluto":"Provisional","Cota del apoyo de visualización (m)":288.1,"Desplazamiento aplicado a la malla (m)":2.0000000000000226,"Criterio":"Nivel de apoyo relativo documentado. Se adopta el cero de proceso a 286,10 m solo para visualización; la equivalencia absoluta no está confirmada. No se añade un espesor de montaje sin cota del fabricante."} | ["La masa de 5 750 kg por unidad es el reparto uniforme de 23 000 kg del conjunto; confirmar el reparto real de cargas. Barandillas y sombreretes no se detallan.","El detalle de abril presenta una célula de 5,85 × 2,20 m; el contorno de agosto es de 5,85 × 2,14 m. Se usa el contorno de agosto. El ventilador se traslada al nuevo centro sin alterar su diámetro ni sus palas.","Las cotas intermedias 3,20 / 3,40 / 3,52 / 3,56 m no aparecen acotadas en el fabricante.","Espesor de palas de 0,04 m y altura del aro de 0,30 m: hipótesis de visualización.","La sección y altura reales de la estructura y de los paneles permanecen sin confirmar.","Los 25 pilares DZ9 terminan en +2,000; los cinco muros transversales terminan en +1,000. La instalación se asocia a los pilares superiores. El plano conserva -2,200 frente al fondo -2,000 de la sección.","El cero absoluto de la revisión no está definido; 286,10 m sigue siendo una hipótesis de coordinación.","Se alinea el punto inferior del conjunto del equipo, incluidos los pies ya representados, con la superficie de apoyo terminada; no se añade un espesor de calzos, placa o grout del fabricante no documentado."] | {"revision":"Detalle en planta de 2026-04-30 coordinado de forma preliminar con envolventes y alturas de 2026-08-25","status":"provisional","verticalRule":"Altura total documentada: 3,70 m. Distribución conceptual: cuerpo 0–3,20 m; plataforma superior 3,20–3,40 m; aro del ventilador 3,40–3,70 m; palas 3,52–3,56 m.","partCount":12,"source":{"documentId":"EQ-IMPLANTACION-20260430","title":"Plano del fabricante: implantación de equipos","sheet":"LHD2609-GD01000 · espacio modelo","date":"2026-04-30"},"heightSource":{"documentId":"EQ-CARGAS-20260825","title":"Plano del fabricante: cargas de equipos","sheet":"Espacio modelo","date":"2026-08-25"},"unconfirmedDimensions":["Las cotas intermedias 3,20 / 3,40 / 3,52 / 3,56 m no aparecen acotadas en el fabricante.","Espesor de palas de 0,04 m y altura del aro de 0,30 m: hipótesis de visualización.","La sección y altura reales de la estructura y de los paneles permanecen sin confirmar."],"quantityUse":"Magnitudes de la geometría representada; no son cantidades de material, obra, compra, capacidad útil ni fabricación. En geometrías compuestas se suman superficies y volúmenes de partes y pueden existir solapes no depurados.","partsAreBOM":false} | equipment_component | {"min":[35.861928,42.104178,3.1],"max":[41.948887,45.021028,6.8]} | {"boundingBoxM":{"min":[35.861928,42.104178,3.1],"max":[41.948887,45.021028,6.8]},"extentsM":[6.086959,2.9168500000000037,3.6999999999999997],"meshSurfaceM2":106.95190117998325,"meshVolumeM3":42.214443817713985,"closedSolid":true,"windingConsistent":true,"basis":"Submalla exacta de los triángulos del modelo IFC coordinado; separación de componentes sin transformación ni retesselación."} | ["Las cotas intermedias 3,20 / 3,40 / 3,52 / 3,56 m no aparecen acotadas en el fabricante.","Espesor de palas de 0,04 m y altura del aro de 0,30 m: hipótesis de visualización.","La sección y altura reales de la estructura y de los paneles permanecen sin confirmar.","La separación gráfica no aporta cotas de fabricación ni identifica piezas internas no documentadas.","Los materiales y acabados permanecen provisionales; las fotografías públicas solo orientan la apariencia."] | {"id":"WT3001D--blade-03","sourcePartId":"WT3001D--blade-03","name":"Pala de ventilador 3 · contorno CAD","role":"equipment_component","classificationStatus":"provisional","classificationBasis":"Rol del subvolumen gráfico según el activo de detalle; identidad de fabricación no confirmada.","parentEquipmentId":"WT3001D","parentEquipmentGuid":"2AZFhKNMnMognqXDVjGcnW","isAssemblyIdentityCarrier":false,"sourceFaceRange":[2372,2392],"sourceCurrentFaceIndices":[2372,2373,2374,2375,2376,2377,2378,2379,2380,2381,2382,2383,2384,2385,2386,2387,2388,2389,2390,2391],"sourceMeshSha256":"7b60c904c9d84d22fded9be34af09a09a9c198ec8e75e61902634d5e4064c761","sourceVertexIndices":[1192,1193,1194,1195,1196,1197,1198,1199,1200,1201,1202,1203],"separationMethod":"Partición exacta de triángulos existentes; coordenadas y orientación de caras conservadas.","quantityUse":"Magnitudes geométricas del subvolumen; no son cantidades netas de material, fabricación, suministro o capacidad."} | {"id":"WT3001D","name":"Torre de refrigeración WT3001D","relationship":"decomposed_component","parentShapeMeaning":"La forma del objeto que conserva el ID del equipo es únicamente su componente principal; el conjunto completo requiere sus hijos."} | {"kind":"through_parent","parentEquipmentId":"WT3001D","directAnchorageVerified":false,"note":"La relación del conjunto con cimentaciones se conserva en el objeto que mantiene el ID del equipo; no se atribuye fijación directa a cada subcomponente."} | Documento de implantación y apoyo del conjunto padre; no acredita fijación individual de este componente. | WT3001D--blade-03 | Pala de ventilador 3 · contorno CAD | Equipos | unknown | equipment_silver | {"documentId":"EQ-IMPLANTACION-20260430","title":"Plano del fabricante: implantación de equipos","sheet":"LHD2609-GD01000 · espacio modelo","date":"2026-04-30","componentSourceHandles":["70956"]} | Submalla de triángulos existentes; no hay nueva posición ni nuevas caras. | Cotas globales del conjunto conservadas aparte; las dimensiones de esta ficha son de la submalla. | Coordinación del conjunto padre; anclaje directo individual no acreditado. | Superficie y volumen geométricos brutos; no constituyen cantidades netas de obra, material o fabricación. | Plano general y dimensiones globales de WT3001D; no se asignan esas dimensiones globales a este componente. | ["70956"] | 1 | no | Submalla exacta; interpretación funcional y cotas parciales provisionales.
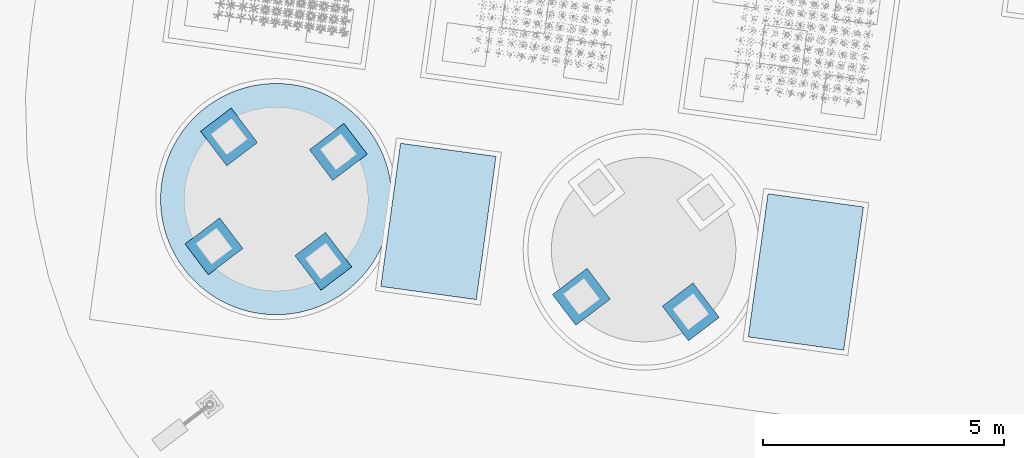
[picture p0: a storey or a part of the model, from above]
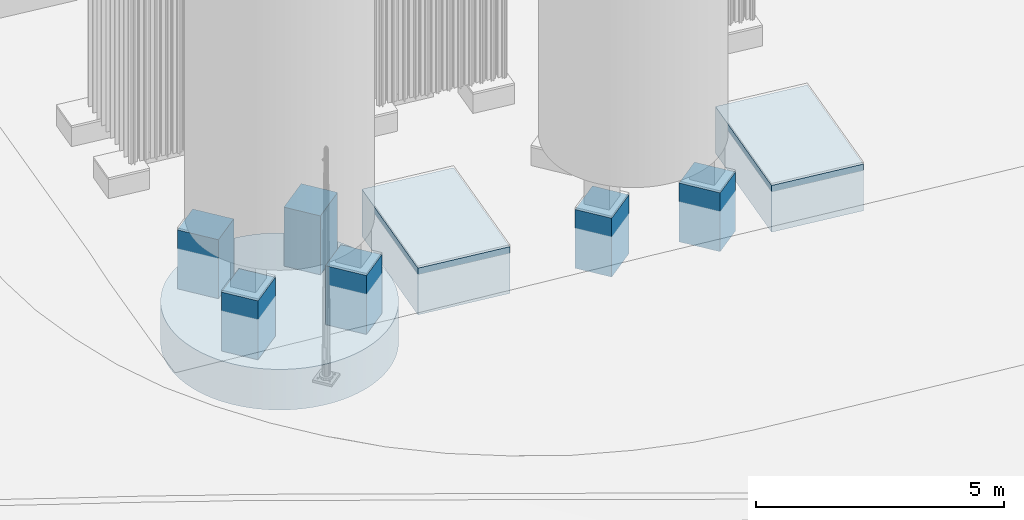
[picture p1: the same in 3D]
Properties of the parts of a building model (IFC4), part 22 of 134

# IfcBuildingElementProxy (140)
Name | Description | Document | Extensión de la malla en X (m) = ExtensionX (m) | Extensión de la malla en Y (m) = ExtensionY (m) | Extensión de la malla en Z (m) = ExtensionZ (m) | Cota inferior de visualización (m) | Cota superior de visualización (m) | SuperficieDeLaMalla (m2) | VolumenGeometrico (m3) | level | category = Categoria = Funcion | representationKind | material | dimensions | JH_InformacionBIM, source = DocumentoFuente | positioning = PosicionYEstado | issues | detailGeometry | geometryMetrics | installationSource | layerId = IdentificadorCapa | visualLayer | materialAppearance | componentSeparation | visualizationIdentity | classification | appearance | Disciplina | Material | Capa BIM = NombreCapa | Acabado de visualización = Acabado | Estado del acabado = Estado | Identificador | JH_Trazabilidad, IncidenciasPendientes | UsoDeLasMagnitudes | JH_EvidenciaDeMaterial, source | JH_DetalleGeometrico, source | VisibilidadInicial | Perfil | ColorRGB | Rugosidad | Metallicidad | Referencia | Nota | Group | parentEquipmentId = Identificador del equipo padre | parentEquipmentName = Equipo padre | parentEquipmentIfcClass | parentEquipmentDimensions | parentEquipmentPositioning | parentEquipmentIssues | parentEquipmentDetail | componentRole = Rol del componente | assemblyBBox | assemblyGeometryMetrics | manufacturerDetailsPending | component | assembly | foundationRelationship | installationSourceScope | Identificador del elemento = sourcePartId | Componente | Capa de visualización | Estado del material | Perfil visual del material | Fuente del componente | Criterio de partición | Criterio de las dimensiones | Relación con cimentaciones | Aplicabilidad de las mediciones | Referencia dimensional del conjunto | sourceHandles | partCount | partsAreBOM | status
Depósito de nitrógeno líquido SV1801A · Envolvente de apoyo 4 · huella real en planta | Componente de equipo · cuerpo o accesorio | Plano del fabricante: implantación de equipos · referencia E7 | 0.770459 | 0.770459 | 0.6 | 286.6 | 287.2 | 1.92464 | 0.181448 | Apoyo relativo +0.500 m; cero absoluto provisional | Componente de equipo · cuerpo o accesorio | equipmentComponent | {"name":"No especificado","source":"Sin especificación de material en la documentación revisada","status":"unknown"} | {"documented":[{"label":"Referencia dimensional del conjunto","value":"Plano general y dimensiones globales de SV1801A; no se asignan esas dimensiones globales a este componente.","unit":"","source":"EQ-IMPLANTACION-20260430 · LHD2609-GD01000 · espacio modelo","status":"referencia_del_conjunto"}],"geometry":[{"label":"Extensión de la malla en X","value":0.7704590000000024,"unit":"m","source":"Geometría releída del IFC; datum absoluto de proceso provisional","status":"derivado"},{"label":"Extensión de la malla en Y","value":0.7704589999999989,"unit":"m","source":"Geometría releída del IFC; datum absoluto de proceso provisional","status":"derivado"},{"label":"Extensión de la malla en Z","value":0.6000000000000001,"unit":"m","source":"Geometría releída del IFC; datum absoluto de proceso provisional","status":"derivado"},{"label":"Cota inferior de visualización","value":286.6,"unit":"m","source":"Geometría releída del IFC; datum absoluto de proceso provisional","status":"derivado"},{"label":"Cota superior de visualización","value":287.2,"unit":"m","source":"Geometría releída del IFC; datum absoluto de proceso provisional","status":"derivado"}],"notes":["Las dimensiones del equipo completo se conservan en parentEquipmentDimensions.","Las extensiones en X/Y son de los ejes del modelo y no sustituyen cotas locales de fabricación.","No se infieren espesores de chapa, tolerancias ni dimensiones de piezas a partir de la partición."]} | {"documentId":"EQ-IMPLANTACION-20260430","title":"Plano del fabricante: implantación de equipos","sheet":"LHD2609-GD01000 · espacio modelo","date":"2026-04-30","componentSourceHandles":["69AC7"]} | {"horizontalStatus":"derivado_del_conjunto","verticalStatus":"derivado_del_conjunto","coordinateSystem":"model_local_m","parentEquipmentId":"SV1801A","transformApplied":false,"note":"Coordenadas copiadas exactamente del equipo coordinado; no se ha movido, girado, elevado ni reescalado este componente.","foundationRelationship":"El apoyo y las cotas de instalación se documentan para el conjunto padre. Esta submalla no acredita un anclaje directo.","meshMinimumAbsoluteElevationM":286.6,"assemblyPlacementField":"parentEquipmentPositioning"} | ["Componente separado de una reconstrucción documental del conjunto. Las alturas y detalles parciales conservan las limitaciones del fabricante registradas en parentEquipmentIssues.","Esta representación exterior no crea una chapa hueca ni añade componentes internos no documentados.","La pertenencia al conjunto no demuestra apoyo o anclaje directo a la cimentación."] | {"source":{"documentId":"EQ-IMPLANTACION-20260430","title":"Plano del fabricante: implantación de equipos","sheet":"LHD2609-GD01000 · espacio modelo","date":"2026-04-30","componentSourceHandles":["69AC7"]},"sourcePartId":"SV1801A--support-04","sourceHandles":["69AC7"],"partCount":1,"partsAreBOM":false,"status":"Submalla exacta; interpretación funcional y cotas parciales provisionales."} | {"boundingBoxM":{"min":[34.702994,31.155127,1.6],"max":[35.473453,31.925586,2.2]},"extentsM":[0.770459,0.770459,0.6],"meshSurfaceM2":1.92464,"meshVolumeM3":0.181448,"closedSolid":true,"basis":"Geometría de coordinación. Los volúmenes de referencia y subcomponentes no son cantidades de material ni componentes de fabricación certificados."} | {"documentId":"LHD2609-JG00100-20260904","title":"Cimentaciones y pedestales de equipos · revisión recibida 04/09/2026","date":"2026-09-04","sheet":"7 / 7-7","sourceHandles":["1FEDA","1FF68"]} | equipment | {"id":"equipment","name":"Equipos"} | {"profileId":"equipment_dark_frame","name":"Bastidor metálico · gris oscuro provisional","materialName":"No especificado","physicalMaterialStatus":"unknown","physicalMaterialSource":"Sin especificación de material en la documentación revisada","appearanceStatus":"provisional","appearanceBasis":"Referencia visual de fotografías públicas de Jinhong Gas / fabricante. Apariencia provisional para coordinación; fotografías oficiales pueden orientar el color, pero no acreditan el material, el acabado ni el equipo concreto.","appearanceReferences":["jinhong-official-asu"],"note":"El perfil visual no confirma material, grado ni acabado del componente."} | {"status":"componente_independiente","note":"Objeto independiente seleccionable. Las caras se asignan una sola vez entre todos los componentes del conjunto.","parentEquipmentId":"SV1801A","isAssemblyIdentityCarrier":false} | {"elementId":"SV1801A--support-04","ifcGuid":"01OPf5K_zGr8Alfll7Wgu$","ifcClass":"IfcBuildingElementProxy","buildingId":"process_plant","buildingName":"Planta de proceso","sourceDocumentId":"EQ-IMPLANTACION-20260430","sourceRepresentationKind":"equipmentComponent"} | {"layerId":"equipment","layerName":"Equipos","role":"Componente de equipo · cuerpo o accesorio","basis":"Clasificación por función del elemento; no modifica las especificaciones documentales."} | {"profileId":"equipment_dark_frame","name":"Bastidor metálico · gris oscuro provisional","status":"provisional","basis":"Referencia visual de fotografías públicas de Jinhong Gas / fabricante. Apariencia provisional para coordinación; fotografías oficiales pueden orientar el color, pero no acreditan el material, el acabado ni el equipo concreto.","physicalMaterialUnchanged":true} | Equipos | No especificado | Equipos | Bastidor metálico · gris oscuro provisional | provisional | SV1801A--support-04 | ["Componente separado de una reconstrucción documental del conjunto. Las alturas y detalles parciales conservan las limitaciones del fabricante registradas en parentEquipmentIssues.","Esta representación exterior no crea una chapa hueca ni añade componentes internos no documentados.","La pertenencia al conjunto no demuestra apoyo o anclaje directo a la cimentación."] | Geometría de coordinación. Los volúmenes de referencia y subcomponentes no son cantidades de material ni componentes de fabricación certificados. | Sin especificación de material en la documentación revisada | {"documentId":"EQ-IMPLANTACION-20260430","title":"Plano del fabricante: implantación de equipos","sheet":"LHD2609-GD01000 · espacio modelo","date":"2026-04-30","componentSourceHandles":["69AC7"]} | yes | equipment_dark_frame | [0.290196,0.329412,0.34902] | 0.62 | 0.5 | Referencia visual de fotografías públicas de Jinhong Gas / fabricante. Apariencia provisional para coordinación; fotografías oficiales pueden orientar el color, pero no acreditan el material, el acabado ni el equipo concreto. | La apariencia no certifica el material físico ni el acabado de fabricación. | BIM · Equipos | SV1801A | Depósito de nitrógeno líquido SV1801A | IfcTank | {"documented":[{"label":"Diámetro exterior del contorno CAD","value":3.828,"unit":"m","source":"EQ-CARGAS-20260825 · contorno CAD · handles 42F","status":"derivado"},{"label":"Altura acotada","value":22.027,"unit":"m","source":"EQ-CARGAS-20260825 · handle 434","status":"documentado"},{"label":"Cota relativa de la superficie de apoyo","value":0.5,"unit":"m","source":"LHD2609-JG00100-20260904 · sección 7 / 7-7 · 1FEDA, 1FF68","status":"documentado"}],"geometry":[{"label":"Extensión de la malla en X","value":3.827938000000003,"unit":"m","source":"Geometría releída del IFC; datum absoluto de proceso provisional","status":"derivado"},{"label":"Extensión de la malla en Y","value":3.827936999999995,"unit":"m","source":"Geometría releída del IFC; datum absoluto de proceso provisional","status":"derivado"},{"label":"Extensión de la malla en Z","value":22.026999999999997,"unit":"m","source":"Geometría releída del IFC; datum absoluto de proceso provisional","status":"derivado"},{"label":"Cota inferior de visualización","value":286.6,"unit":"m","source":"Geometría releída del IFC; datum absoluto de proceso provisional","status":"derivado"},{"label":"Cota superior de visualización","value":308.627,"unit":"m","source":"Geometría releída del IFC; datum absoluto de proceso provisional","status":"derivado"}],"notes":["Las extensiones de la malla se miden en los ejes del proyecto tras el giro de implantación; no sustituyen las dimensiones locales del fabricante.","La envolvente, su volumen y los espesores de visualización no son volúmenes de material ni cantidades de compra, construcción o fabricación.","Las dimensiones documentadas distinguen cotas explícitas y medidas extraídas de contornos CAD; las dimensiones geométricas describen únicamente la malla publicada.","Las extensiones de la malla refinada y las dimensiones documentadas del contorno o bastidor tienen distinto alcance; las cotas parciales del detalle son provisionales."]} | {"Estado de la planta":"Derivado del CAD y del giro de implantación","Nivel relativo del apoyo (m)":0.5,"Estado del nivel relativo":"Documentado en el plano de cimentaciones","Cero absoluto de visualización (m)":286.1,"Estado del cero absoluto":"Provisional","Cota del apoyo de visualización (m)":286.6,"Desplazamiento aplicado a la malla (m)":0.5000000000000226,"Criterio":"Nivel de apoyo relativo documentado. Se adopta el cero de proceso a 286,10 m solo para visualización; la equivalencia absoluta no está confirmada. No se añade un espesor de montaje sin cota del fabricante."} | ["Cilindro envolvente de altura total; no se dispone de la forma de los fondos, espesores ni componentes internos. El volumen geométrico no es capacidad útil.","Altura de apoyo de 0,60 m no acotada: hipótesis gráfica.","La planta de los apoyos no confirma su sección ni su construcción a lo largo de la altura.","Geometría de fondos curvos, faldón, soldaduras y espesores sin definir. No se inventan casquetes.","Cuatro pedestales DZ7 por tanque; el acabado superior de grout termina en +0,500. La cota -0,200 de planta no concuerda con -1,000 en la cara superior de la zapata de sección.","El cero absoluto de la revisión no está definido; 286,10 m sigue siendo una hipótesis de coordinación.","Se alinea el punto inferior del conjunto del equipo, incluidos los pies ya representados, con la superficie de apoyo terminada; no se añade un espesor de calzos, placa o grout del fabricante no documentado."] | {"revision":"Detalle en planta de 2026-04-30 coordinado de forma preliminar con envolventes y alturas de 2026-08-25","status":"provisional","verticalRule":"Altura total documentada: 22,027 m y diámetro exterior 3,828 m. Para hacer visibles los apoyos se adopta provisionalmente una altura de apoyo de 0,60 m; envolvente cilíndrica desde Z = 0,60 hasta 22,027 m.","partCount":5,"source":{"documentId":"EQ-IMPLANTACION-20260430","title":"Plano del fabricante: implantación de equipos","sheet":"LHD2609-GD01000 · espacio modelo","date":"2026-04-30"},"heightSource":{"documentId":"EQ-CARGAS-20260825","title":"Plano del fabricante: cargas de equipos","sheet":"Espacio modelo","date":"2026-08-25"},"unconfirmedDimensions":["Altura de apoyo de 0,60 m no acotada: hipótesis gráfica.","La planta de los apoyos no confirma su sección ni su construcción a lo largo de la altura.","Geometría de fondos curvos, faldón, soldaduras y espesores sin definir. No se inventan casquetes."],"quantityUse":"Magnitudes de la geometría representada; no son cantidades de material, obra, compra, capacidad útil ni fabricación. En geometrías compuestas se suman superficies y volúmenes de partes y pueden existir solapes no depurados.","partsAreBOM":false} | equipment_component | {"min":[34.463015,30.600052,1.6],"max":[38.290953,34.427989,23.627]} | {"boundingBoxM":{"min":[34.463015,30.600052,1.6],"max":[38.290953,34.427989,23.627]},"extentsM":[3.827938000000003,3.827936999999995,22.026999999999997],"meshSurfaceM2":288.3822067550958,"meshVolumeM3":247.2829421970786,"closedSolid":true,"windingConsistent":true,"basis":"Submalla exacta de los triángulos del modelo IFC coordinado; separación de componentes sin transformación ni retesselación."} | ["Altura de apoyo de 0,60 m no acotada: hipótesis gráfica.","La planta de los apoyos no confirma su sección ni su construcción a lo largo de la altura.","Geometría de fondos curvos, faldón, soldaduras y espesores sin definir. No se inventan casquetes.","La separación gráfica no aporta cotas de fabricación ni identifica piezas internas no documentadas.","Los materiales y acabados permanecen provisionales; las fotografías públicas solo orientan la apariencia."] | {"id":"SV1801A--support-04","sourcePartId":"SV1801A--support-04","name":"Envolvente de apoyo 4 · huella real en planta","role":"equipment_component","classificationStatus":"provisional","classificationBasis":"Rol del subvolumen gráfico según el activo de detalle; identidad de fabricación no confirmada.","parentEquipmentId":"SV1801A","parentEquipmentGuid":"1EEV2pFbzMUQXwXeX6CZae","isAssemblyIdentityCarrier":false,"sourceFaceRange":[800,812],"sourceCurrentFaceIndices":[800,801,802,803,804,805,806,807,808,809,810,811],"sourceMeshSha256":"7b60c904c9d84d22fded9be34af09a09a9c198ec8e75e61902634d5e4064c761","sourceVertexIndices":[408,409,410,411,412,413,414,415],"separationMethod":"Partición exacta de triángulos existentes; coordenadas y orientación de caras conservadas.","quantityUse":"Magnitudes geométricas del subvolumen; no son cantidades netas de material, fabricación, suministro o capacidad."} | {"id":"SV1801A","name":"Depósito de nitrógeno líquido SV1801A","relationship":"decomposed_component","parentShapeMeaning":"La forma del objeto que conserva el ID del equipo es únicamente su componente principal; el conjunto completo requiere sus hijos."} | {"kind":"through_parent","parentEquipmentId":"SV1801A","directAnchorageVerified":false,"note":"La relación del conjunto con cimentaciones se conserva en el objeto que mantiene el ID del equipo; no se atribuye fijación directa a cada subcomponente."} | Documento de implantación y apoyo del conjunto padre; no acredita fijación individual de este componente. | SV1801A--support-04 | Envolvente de apoyo 4 · huella real en planta | Equipos | unknown | equipment_dark_frame | {"documentId":"EQ-IMPLANTACION-20260430","title":"Plano del fabricante: implantación de equipos","sheet":"LHD2609-GD01000 · espacio modelo","date":"2026-04-30","componentSourceHandles":["69AC7"]} | Submalla de triángulos existentes; no hay nueva posición ni nuevas caras. | Cotas globales del conjunto conservadas aparte; las dimensiones de esta ficha son de la submalla. | Coordinación del conjunto padre; anclaje directo individual no acreditado. | Superficie y volumen geométricos brutos; no constituyen cantidades netas de obra, material o fabricación. | Plano general y dimensiones globales de SV1801A; no se asignan esas dimensiones globales a este componente. | ["69AC7"] | 1 | no | Submalla exacta; interpretación funcional y cotas parciales provisionales.
Depósito de nitrógeno líquido SV1801B · Envolvente de apoyo 1 · huella real en planta | Componente de equipo · cuerpo o accesorio | Plano del fabricante: implantación de equipos · referencia E7 | 0.770459 | 0.770459 | 0.6 | 286.6 | 287.2 | 1.92464 | 0.181448 | Apoyo relativo +0.500 m; cero absoluto provisional | Componente de equipo · cuerpo o accesorio | equipmentComponent | {"name":"No especificado","source":"Sin especificación de material en la documentación revisada","status":"unknown"} | {"documented":[{"label":"Referencia dimensional del conjunto","value":"Plano general y dimensiones globales de SV1801B; no se asignan esas dimensiones globales a este componente.","unit":"","source":"EQ-IMPLANTACION-20260430 · LHD2609-GD01000 · espacio modelo","status":"referencia_del_conjunto"}],"geometry":[{"label":"Extensión de la malla en X","value":0.7704589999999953,"unit":"m","source":"Geometría releída del IFC; datum absoluto de proceso provisional","status":"derivado"},{"label":"Extensión de la malla en Y","value":0.7704590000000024,"unit":"m","source":"Geometría releída del IFC; datum absoluto de proceso provisional","status":"derivado"},{"label":"Extensión de la malla en Z","value":0.6000000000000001,"unit":"m","source":"Geometría releída del IFC; datum absoluto de proceso provisional","status":"derivado"},{"label":"Cota inferior de visualización","value":286.6,"unit":"m","source":"Geometría releída del IFC; datum absoluto de proceso provisional","status":"derivado"},{"label":"Cota superior de visualización","value":287.2,"unit":"m","source":"Geometría releída del IFC; datum absoluto de proceso provisional","status":"derivado"}],"notes":["Las dimensiones del equipo completo se conservan en parentEquipmentDimensions.","Las extensiones en X/Y son de los ejes del modelo y no sustituyen cotas locales de fabricación.","No se infieren espesores de chapa, tolerancias ni dimensiones de piezas a partir de la partición."]} | {"documentId":"EQ-IMPLANTACION-20260430","title":"Plano del fabricante: implantación de equipos","sheet":"LHD2609-GD01000 · espacio modelo","date":"2026-04-30","componentSourceHandles":["69AB8"]} | {"horizontalStatus":"derivado_del_conjunto","verticalStatus":"derivado_del_conjunto","coordinateSystem":"model_local_m","parentEquipmentId":"SV1801B","transformApplied":false,"note":"Coordenadas copiadas exactamente del equipo coordinado; no se ha movido, girado, elevado ni reescalado este componente.","foundationRelationship":"El apoyo y las cotas de instalación se documentan para el conjunto padre. Esta submalla no acredita un anclaje directo.","meshMinimumAbsoluteElevationM":286.6,"assemblyPlacementField":"parentEquipmentPositioning"} | ["Componente separado de una reconstrucción documental del conjunto. Las alturas y detalles parciales conservan las limitaciones del fabricante registradas en parentEquipmentIssues.","Esta representación exterior no crea una chapa hueca ni añade componentes internos no documentados.","La pertenencia al conjunto no demuestra apoyo o anclaje directo a la cimentación."] | {"source":{"documentId":"EQ-IMPLANTACION-20260430","title":"Plano del fabricante: implantación de equipos","sheet":"LHD2609-GD01000 · espacio modelo","date":"2026-04-30","componentSourceHandles":["69AB8"]},"sourcePartId":"SV1801B--support-01","sourceHandles":["69AB8"],"partCount":1,"partsAreBOM":false,"status":"Submalla exacta; interpretación funcional y cotas parciales provisionales."} | {"boundingBoxM":{"min":[44.911768,32.063733,1.6],"max":[45.682227,32.834192,2.2]},"extentsM":[0.770459,0.770459,0.6],"meshSurfaceM2":1.92464,"meshVolumeM3":0.181448,"closedSolid":true,"basis":"Geometría de coordinación. Los volúmenes de referencia y subcomponentes no son cantidades de material ni componentes de fabricación certificados."} | {"documentId":"LHD2609-JG00100-20260904","title":"Cimentaciones y pedestales de equipos · revisión recibida 04/09/2026","date":"2026-09-04","sheet":"7 / 7-7","sourceHandles":["1FEDA","1FF68"]} | equipment | {"id":"equipment","name":"Equipos"} | {"profileId":"equipment_dark_frame","name":"Bastidor metálico · gris oscuro provisional","materialName":"No especificado","physicalMaterialStatus":"unknown","physicalMaterialSource":"Sin especificación de material en la documentación revisada","appearanceStatus":"provisional","appearanceBasis":"Referencia visual de fotografías públicas de Jinhong Gas / fabricante. Apariencia provisional para coordinación; fotografías oficiales pueden orientar el color, pero no acreditan el material, el acabado ni el equipo concreto.","appearanceReferences":["jinhong-official-asu"],"note":"El perfil visual no confirma material, grado ni acabado del componente."} | {"status":"componente_independiente","note":"Objeto independiente seleccionable. Las caras se asignan una sola vez entre todos los componentes del conjunto.","parentEquipmentId":"SV1801B","isAssemblyIdentityCarrier":false} | {"elementId":"SV1801B--support-01","ifcGuid":"0g$3k4AmjHUA0cYRkmqEgO","ifcClass":"IfcBuildingElementProxy","buildingId":"process_plant","buildingName":"Planta de proceso","sourceDocumentId":"EQ-IMPLANTACION-20260430","sourceRepresentationKind":"equipmentComponent"} | {"layerId":"equipment","layerName":"Equipos","role":"Componente de equipo · cuerpo o accesorio","basis":"Clasificación por función del elemento; no modifica las especificaciones documentales."} | {"profileId":"equipment_dark_frame","name":"Bastidor metálico · gris oscuro provisional","status":"provisional","basis":"Referencia visual de fotografías públicas de Jinhong Gas / fabricante. Apariencia provisional para coordinación; fotografías oficiales pueden orientar el color, pero no acreditan el material, el acabado ni el equipo concreto.","physicalMaterialUnchanged":true} | Equipos | No especificado | Equipos | Bastidor metálico · gris oscuro provisional | provisional | SV1801B--support-01 | ["Componente separado de una reconstrucción documental del conjunto. Las alturas y detalles parciales conservan las limitaciones del fabricante registradas en parentEquipmentIssues.","Esta representación exterior no crea una chapa hueca ni añade componentes internos no documentados.","La pertenencia al conjunto no demuestra apoyo o anclaje directo a la cimentación."] | Geometría de coordinación. Los volúmenes de referencia y subcomponentes no son cantidades de material ni componentes de fabricación certificados. | Sin especificación de material en la documentación revisada | {"documentId":"EQ-IMPLANTACION-20260430","title":"Plano del fabricante: implantación de equipos","sheet":"LHD2609-GD01000 · espacio modelo","date":"2026-04-30","componentSourceHandles":["69AB8"]} | yes | equipment_dark_frame | [0.290196,0.329412,0.34902] | 0.62 | 0.5 | Referencia visual de fotografías públicas de Jinhong Gas / fabricante. Apariencia provisional para coordinación; fotografías oficiales pueden orientar el color, pero no acreditan el material, el acabado ni el equipo concreto. | La apariencia no certifica el material físico ni el acabado de fabricación. | BIM · Equipos | SV1801B | Depósito de nitrógeno líquido SV1801B | IfcTank | {"documented":[{"label":"Diámetro exterior del contorno CAD","value":3.828,"unit":"m","source":"EQ-CARGAS-20260825 · contorno CAD · handles 438","status":"derivado"},{"label":"Altura acotada","value":22.027,"unit":"m","source":"EQ-CARGAS-20260825 · handle 273B","status":"documentado"},{"label":"Cota relativa de la superficie de apoyo","value":0.5,"unit":"m","source":"LHD2609-JG00100-20260904 · sección 7 / 7-7 · 1FEDA, 1FF68","status":"documentado"}],"geometry":[{"label":"Extensión de la malla en X","value":3.8279369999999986,"unit":"m","source":"Geometría releída del IFC; datum absoluto de proceso provisional","status":"derivado"},{"label":"Extensión de la malla en Y","value":3.8279379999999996,"unit":"m","source":"Geometría releída del IFC; datum absoluto de proceso provisional","status":"derivado"},{"label":"Extensión de la malla en Z","value":22.026999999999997,"unit":"m","source":"Geometría releída del IFC; datum absoluto de proceso provisional","status":"derivado"},{"label":"Cota inferior de visualización","value":286.6,"unit":"m","source":"Geometría releída del IFC; datum absoluto de proceso provisional","status":"derivado"},{"label":"Cota superior de visualización","value":308.627,"unit":"m","source":"Geometría releída del IFC; datum absoluto de proceso provisional","status":"derivado"}],"notes":["Las extensiones de la malla se miden en los ejes del proyecto tras el giro de implantación; no sustituyen las dimensiones locales del fabricante.","La envolvente, su volumen y los espesores de visualización no son volúmenes de material ni cantidades de compra, construcción o fabricación.","Las dimensiones documentadas distinguen cotas explícitas y medidas extraídas de contornos CAD; las dimensiones geométricas describen únicamente la malla publicada.","Las extensiones de la malla refinada y las dimensiones documentadas del contorno o bastidor tienen distinto alcance; las cotas parciales del detalle son provisionales."]} | {"Estado de la planta":"Derivado del CAD y del giro de implantación","Nivel relativo del apoyo (m)":0.5,"Estado del nivel relativo":"Documentado en el plano de cimentaciones","Cero absoluto de visualización (m)":286.1,"Estado del cero absoluto":"Provisional","Cota del apoyo de visualización (m)":286.6,"Desplazamiento aplicado a la malla (m)":0.5000000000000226,"Criterio":"Nivel de apoyo relativo documentado. Se adopta el cero de proceso a 286,10 m solo para visualización; la equivalencia absoluta no está confirmada. No se añade un espesor de montaje sin cota del fabricante."} | ["Cilindro envolvente de altura total; no se dispone de la forma de los fondos, espesores ni componentes internos. El volumen geométrico no es capacidad útil.","Altura de apoyo de 0,60 m no acotada: hipótesis gráfica.","La planta de los apoyos no confirma su sección ni su construcción a lo largo de la altura.","Geometría de fondos curvos, faldón, soldaduras y espesores sin definir. No se inventan casquetes.","Cuatro pedestales DZ7 por tanque; el acabado superior de grout termina en +0,500. La cota -0,200 de planta no concuerda con -1,000 en la cara superior de la zapata de sección.","El cero absoluto de la revisión no está definido; 286,10 m sigue siendo una hipótesis de coordinación.","Se alinea el punto inferior del conjunto del equipo, incluidos los pies ya representados, con la superficie de apoyo terminada; no se añade un espesor de calzos, placa o grout del fabricante no documentado."] | {"revision":"Detalle en planta de 2026-04-30 coordinado de forma preliminar con envolventes y alturas de 2026-08-25","status":"provisional","verticalRule":"Altura total documentada: 22,027 m y diámetro exterior 3,828 m. Para hacer visibles los apoyos se adopta provisionalmente una altura de apoyo de 0,60 m; envolvente cilíndrica desde Z = 0,60 hasta 22,027 m.","partCount":5,"source":{"documentId":"EQ-IMPLANTACION-20260430","title":"Plano del fabricante: implantación de equipos","sheet":"LHD2609-GD01000 · espacio modelo","date":"2026-04-30"},"heightSource":{"documentId":"EQ-CARGAS-20260825","title":"Plano del fabricante: cargas de equipos","sheet":"Espacio modelo","date":"2026-08-25"},"unconfirmedDimensions":["Altura de apoyo de 0,60 m no acotada: hipótesis gráfica.","La planta de los apoyos no confirma su sección ni su construcción a lo largo de la altura.","Geometría de fondos curvos, faldón, soldaduras y espesores sin definir. No se inventan casquetes."],"quantityUse":"Magnitudes de la geometría representada; no son cantidades de material, obra, compra, capacidad útil ni fabricación. En geometrías compuestas se suman superficies y volúmenes de partes y pueden existir solapes no depurados.","partsAreBOM":false} | equipment_component | {"min":[42.091258,29.551281,1.6],"max":[45.919195,33.379219,23.627]} | {"boundingBoxM":{"min":[42.091258,29.551281,1.6],"max":[45.919195,33.379219,23.627]},"extentsM":[3.8279369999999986,3.8279379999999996,22.026999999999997],"meshSurfaceM2":288.3822071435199,"meshVolumeM3":247.2829421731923,"closedSolid":true,"windingConsistent":true,"basis":"Submalla exacta de los triángulos del modelo IFC coordinado; separación de componentes sin transformación ni retesselación."} | ["Altura de apoyo de 0,60 m no acotada: hipótesis gráfica.","La planta de los apoyos no confirma su sección ni su construcción a lo largo de la altura.","Geometría de fondos curvos, faldón, soldaduras y espesores sin definir. No se inventan casquetes.","La separación gráfica no aporta cotas de fabricación ni identifica piezas internas no documentadas.","Los materiales y acabados permanecen provisionales; las fotografías públicas solo orientan la apariencia."] | {"id":"SV1801B--support-01","sourcePartId":"SV1801B--support-01","name":"Envolvente de apoyo 1 · huella real en planta","role":"equipment_component","classificationStatus":"provisional","classificationBasis":"Rol del subvolumen gráfico según el activo de detalle; identidad de fabricación no confirmada.","parentEquipmentId":"SV1801B","parentEquipmentGuid":"206t194YPQWO6Wa6jSddOs","isAssemblyIdentityCarrier":false,"sourceFaceRange":[764,776],"sourceCurrentFaceIndices":[764,765,766,767,768,769,770,771,772,773,774,775],"sourceMeshSha256":"7b60c904c9d84d22fded9be34af09a09a9c198ec8e75e61902634d5e4064c761","sourceVertexIndices":[384,385,386,387,388,389,390,391],"separationMethod":"Partición exacta de triángulos existentes; coordenadas y orientación de caras conservadas.","quantityUse":"Magnitudes geométricas del subvolumen; no son cantidades netas de material, fabricación, suministro o capacidad."} | {"id":"SV1801B","name":"Depósito de nitrógeno líquido SV1801B","relationship":"decomposed_component","parentShapeMeaning":"La forma del objeto que conserva el ID del equipo es únicamente su componente principal; el conjunto completo requiere sus hijos."} | {"kind":"through_parent","parentEquipmentId":"SV1801B","directAnchorageVerified":false,"note":"La relación del conjunto con cimentaciones se conserva en el objeto que mantiene el ID del equipo; no se atribuye fijación directa a cada subcomponente."} | Documento de implantación y apoyo del conjunto padre; no acredita fijación individual de este componente. | SV1801B--support-01 | Envolvente de apoyo 1 · huella real en planta | Equipos | unknown | equipment_dark_frame | {"documentId":"EQ-IMPLANTACION-20260430","title":"Plano del fabricante: implantación de equipos","sheet":"LHD2609-GD01000 · espacio modelo","date":"2026-04-30","componentSourceHandles":["69AB8"]} | Submalla de triángulos existentes; no hay nueva posición ni nuevas caras. | Cotas globales del conjunto conservadas aparte; las dimensiones de esta ficha son de la submalla. | Coordinación del conjunto padre; anclaje directo individual no acreditado. | Superficie y volumen geométricos brutos; no constituyen cantidades netas de obra, material o fabricación. | Plano general y dimensiones globales de SV1801B; no se asignan esas dimensiones globales a este componente. | ["69AB8"] | 1 | no | Submalla exacta; interpretación funcional y cotas parciales provisionales.
Depósito de nitrógeno líquido SV1801B · Envolvente de apoyo 2 · huella real en planta | Componente de equipo · cuerpo o accesorio | Plano del fabricante: implantación de equipos · referencia E7 | 0.770458 | 0.770458 | 0.6 | 286.6 | 287.2 | 1.92464 | 0.181448 | Apoyo relativo +0.500 m; cero absoluto provisional | Componente de equipo · cuerpo o accesorio | equipmentComponent | {"name":"No especificado","source":"Sin especificación de material en la documentación revisada","status":"unknown"} | {"documented":[{"label":"Referencia dimensional del conjunto","value":"Plano general y dimensiones globales de SV1801B; no se asignan esas dimensiones globales a este componente.","unit":"","source":"EQ-IMPLANTACION-20260430 · LHD2609-GD01000 · espacio modelo","status":"referencia_del_conjunto"}],"geometry":[{"label":"Extensión de la malla en X","value":0.770458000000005,"unit":"m","source":"Geometría releída del IFC; datum absoluto de proceso provisional","status":"derivado"},{"label":"Extensión de la malla en Y","value":0.7704580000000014,"unit":"m","source":"Geometría releída del IFC; datum absoluto de proceso provisional","status":"derivado"},{"label":"Extensión de la malla en Z","value":0.6000000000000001,"unit":"m","source":"Geometría releída del IFC; datum absoluto de proceso provisional","status":"derivado"},{"label":"Cota inferior de visualización","value":286.6,"unit":"m","source":"Geometría releída del IFC; datum absoluto de proceso provisional","status":"derivado"},{"label":"Cota superior de visualización","value":287.2,"unit":"m","source":"Geometría releída del IFC; datum absoluto de proceso provisional","status":"derivado"}],"notes":["Las dimensiones del equipo completo se conservan en parentEquipmentDimensions.","Las extensiones en X/Y son de los ejes del modelo y no sustituyen cotas locales de fabricación.","No se infieren espesores de chapa, tolerancias ni dimensiones de piezas a partir de la partición."]} | {"documentId":"EQ-IMPLANTACION-20260430","title":"Plano del fabricante: implantación de equipos","sheet":"LHD2609-GD01000 · espacio modelo","date":"2026-04-30","componentSourceHandles":["69ABD"]} | {"horizontalStatus":"derivado_del_conjunto","verticalStatus":"derivado_del_conjunto","coordinateSystem":"model_local_m","parentEquipmentId":"SV1801B","transformApplied":false,"note":"Coordenadas copiadas exactamente del equipo coordinado; no se ha movido, girado, elevado ni reescalado este componente.","foundationRelationship":"El apoyo y las cotas de instalación se documentan para el conjunto padre. Esta submalla no acredita un anclaje directo.","meshMinimumAbsoluteElevationM":286.6,"assemblyPlacementField":"parentEquipmentPositioning"} | ["Componente separado de una reconstrucción documental del conjunto. Las alturas y detalles parciales conservan las limitaciones del fabricante registradas en parentEquipmentIssues.","Esta representación exterior no crea una chapa hueca ni añade componentes internos no documentados.","La pertenencia al conjunto no demuestra apoyo o anclaje directo a la cimentación."] | {"source":{"documentId":"EQ-IMPLANTACION-20260430","title":"Plano del fabricante: implantación de equipos","sheet":"LHD2609-GD01000 · espacio modelo","date":"2026-04-30","componentSourceHandles":["69ABD"]},"sourcePartId":"SV1801B--support-02","sourceHandles":["69ABD"],"partCount":1,"partsAreBOM":false,"status":"Submalla exacta; interpretación funcional y cotas parciales provisionales."} | {"boundingBoxM":{"min":[44.599762,29.794351,1.6],"max":[45.37022,30.564809,2.2]},"extentsM":[0.770458,0.770458,0.6],"meshSurfaceM2":1.924637,"meshVolumeM3":0.181448,"closedSolid":true,"basis":"Geometría de coordinación. Los volúmenes de referencia y subcomponentes no son cantidades de material ni componentes de fabricación certificados."} | {"documentId":"LHD2609-JG00100-20260904","title":"Cimentaciones y pedestales de equipos · revisión recibida 04/09/2026","date":"2026-09-04","sheet":"7 / 7-7","sourceHandles":["1FEDA","1FF68"]} | equipment | {"id":"equipment","name":"Equipos"} | {"profileId":"equipment_dark_frame","name":"Bastidor metálico · gris oscuro provisional","materialName":"No especificado","physicalMaterialStatus":"unknown","physicalMaterialSource":"Sin especificación de material en la documentación revisada","appearanceStatus":"provisional","appearanceBasis":"Referencia visual de fotografías públicas de Jinhong Gas / fabricante. Apariencia provisional para coordinación; fotografías oficiales pueden orientar el color, pero no acreditan el material, el acabado ni el equipo concreto.","appearanceReferences":["jinhong-official-asu"],"note":"El perfil visual no confirma material, grado ni acabado del componente."} | {"status":"componente_independiente","note":"Objeto independiente seleccionable. Las caras se asignan una sola vez entre todos los componentes del conjunto.","parentEquipmentId":"SV1801B","isAssemblyIdentityCarrier":false} | {"elementId":"SV1801B--support-02","ifcGuid":"0G7z$7_RnMdhq26piB0hz_","ifcClass":"IfcBuildingElementProxy","buildingId":"process_plant","buildingName":"Planta de proceso","sourceDocumentId":"EQ-IMPLANTACION-20260430","sourceRepresentationKind":"equipmentComponent"} | {"layerId":"equipment","layerName":"Equipos","role":"Componente de equipo · cuerpo o accesorio","basis":"Clasificación por función del elemento; no modifica las especificaciones documentales."} | {"profileId":"equipment_dark_frame","name":"Bastidor metálico · gris oscuro provisional","status":"provisional","basis":"Referencia visual de fotografías públicas de Jinhong Gas / fabricante. Apariencia provisional para coordinación; fotografías oficiales pueden orientar el color, pero no acreditan el material, el acabado ni el equipo concreto.","physicalMaterialUnchanged":true} | Equipos | No especificado | Equipos | Bastidor metálico · gris oscuro provisional | provisional | SV1801B--support-02 | ["Componente separado de una reconstrucción documental del conjunto. Las alturas y detalles parciales conservan las limitaciones del fabricante registradas en parentEquipmentIssues.","Esta representación exterior no crea una chapa hueca ni añade componentes internos no documentados.","La pertenencia al conjunto no demuestra apoyo o anclaje directo a la cimentación."] | Geometría de coordinación. Los volúmenes de referencia y subcomponentes no son cantidades de material ni componentes de fabricación certificados. | Sin especificación de material en la documentación revisada | {"documentId":"EQ-IMPLANTACION-20260430","title":"Plano del fabricante: implantación de equipos","sheet":"LHD2609-GD01000 · espacio modelo","date":"2026-04-30","componentSourceHandles":["69ABD"]} | yes | equipment_dark_frame | [0.290196,0.329412,0.34902] | 0.62 | 0.5 | Referencia visual de fotografías públicas de Jinhong Gas / fabricante. Apariencia provisional para coordinación; fotografías oficiales pueden orientar el color, pero no acreditan el material, el acabado ni el equipo concreto. | La apariencia no certifica el material físico ni el acabado de fabricación. | BIM · Equipos | SV1801B | Depósito de nitrógeno líquido SV1801B | IfcTank | {"documented":[{"label":"Diámetro exterior del contorno CAD","value":3.828,"unit":"m","source":"EQ-CARGAS-20260825 · contorno CAD · handles 438","status":"derivado"},{"label":"Altura acotada","value":22.027,"unit":"m","source":"EQ-CARGAS-20260825 · handle 273B","status":"documentado"},{"label":"Cota relativa de la superficie de apoyo","value":0.5,"unit":"m","source":"LHD2609-JG00100-20260904 · sección 7 / 7-7 · 1FEDA, 1FF68","status":"documentado"}],"geometry":[{"label":"Extensión de la malla en X","value":3.8279369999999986,"unit":"m","source":"Geometría releída del IFC; datum absoluto de proceso provisional","status":"derivado"},{"label":"Extensión de la malla en Y","value":3.8279379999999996,"unit":"m","source":"Geometría releída del IFC; datum absoluto de proceso provisional","status":"derivado"},{"label":"Extensión de la malla en Z","value":22.026999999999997,"unit":"m","source":"Geometría releída del IFC; datum absoluto de proceso provisional","status":"derivado"},{"label":"Cota inferior de visualización","value":286.6,"unit":"m","source":"Geometría releída del IFC; datum absoluto de proceso provisional","status":"derivado"},{"label":"Cota superior de visualización","value":308.627,"unit":"m","source":"Geometría releída del IFC; datum absoluto de proceso provisional","status":"derivado"}],"notes":["Las extensiones de la malla se miden en los ejes del proyecto tras el giro de implantación; no sustituyen las dimensiones locales del fabricante.","La envolvente, su volumen y los espesores de visualización no son volúmenes de material ni cantidades de compra, construcción o fabricación.","Las dimensiones documentadas distinguen cotas explícitas y medidas extraídas de contornos CAD; las dimensiones geométricas describen únicamente la malla publicada.","Las extensiones de la malla refinada y las dimensiones documentadas del contorno o bastidor tienen distinto alcance; las cotas parciales del detalle son provisionales."]} | {"Estado de la planta":"Derivado del CAD y del giro de implantación","Nivel relativo del apoyo (m)":0.5,"Estado del nivel relativo":"Documentado en el plano de cimentaciones","Cero absoluto de visualización (m)":286.1,"Estado del cero absoluto":"Provisional","Cota del apoyo de visualización (m)":286.6,"Desplazamiento aplicado a la malla (m)":0.5000000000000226,"Criterio":"Nivel de apoyo relativo documentado. Se adopta el cero de proceso a 286,10 m solo para visualización; la equivalencia absoluta no está confirmada. No se añade un espesor de montaje sin cota del fabricante."} | ["Cilindro envolvente de altura total; no se dispone de la forma de los fondos, espesores ni componentes internos. El volumen geométrico no es capacidad útil.","Altura de apoyo de 0,60 m no acotada: hipótesis gráfica.","La planta de los apoyos no confirma su sección ni su construcción a lo largo de la altura.","Geometría de fondos curvos, faldón, soldaduras y espesores sin definir. No se inventan casquetes.","Cuatro pedestales DZ7 por tanque; el acabado superior de grout termina en +0,500. La cota -0,200 de planta no concuerda con -1,000 en la cara superior de la zapata de sección.","El cero absoluto de la revisión no está definido; 286,10 m sigue siendo una hipótesis de coordinación.","Se alinea el punto inferior del conjunto del equipo, incluidos los pies ya representados, con la superficie de apoyo terminada; no se añade un espesor de calzos, placa o grout del fabricante no documentado."] | {"revision":"Detalle en planta de 2026-04-30 coordinado de forma preliminar con envolventes y alturas de 2026-08-25","status":"provisional","verticalRule":"Altura total documentada: 22,027 m y diámetro exterior 3,828 m. Para hacer visibles los apoyos se adopta provisionalmente una altura de apoyo de 0,60 m; envolvente cilíndrica desde Z = 0,60 hasta 22,027 m.","partCount":5,"source":{"documentId":"EQ-IMPLANTACION-20260430","title":"Plano del fabricante: implantación de equipos","sheet":"LHD2609-GD01000 · espacio modelo","date":"2026-04-30"},"heightSource":{"documentId":"EQ-CARGAS-20260825","title":"Plano del fabricante: cargas de equipos","sheet":"Espacio modelo","date":"2026-08-25"},"unconfirmedDimensions":["Altura de apoyo de 0,60 m no acotada: hipótesis gráfica.","La planta de los apoyos no confirma su sección ni su construcción a lo largo de la altura.","Geometría de fondos curvos, faldón, soldaduras y espesores sin definir. No se inventan casquetes."],"quantityUse":"Magnitudes de la geometría representada; no son cantidades de material, obra, compra, capacidad útil ni fabricación. En geometrías compuestas se suman superficies y volúmenes de partes y pueden existir solapes no depurados.","partsAreBOM":false} | equipment_component | {"min":[42.091258,29.551281,1.6],"max":[45.919195,33.379219,23.627]} | {"boundingBoxM":{"min":[42.091258,29.551281,1.6],"max":[45.919195,33.379219,23.627]},"extentsM":[3.8279369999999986,3.8279379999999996,22.026999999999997],"meshSurfaceM2":288.3822071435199,"meshVolumeM3":247.2829421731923,"closedSolid":true,"windingConsistent":true,"basis":"Submalla exacta de los triángulos del modelo IFC coordinado; separación de componentes sin transformación ni retesselación."} | ["Altura de apoyo de 0,60 m no acotada: hipótesis gráfica.","La planta de los apoyos no confirma su sección ni su construcción a lo largo de la altura.","Geometría de fondos curvos, faldón, soldaduras y espesores sin definir. No se inventan casquetes.","La separación gráfica no aporta cotas de fabricación ni identifica piezas internas no documentadas.","Los materiales y acabados permanecen provisionales; las fotografías públicas solo orientan la apariencia."] | {"id":"SV1801B--support-02","sourcePartId":"SV1801B--support-02","name":"Envolvente de apoyo 2 · huella real en planta","role":"equipment_component","classificationStatus":"provisional","classificationBasis":"Rol del subvolumen gráfico según el activo de detalle; identidad de fabricación no confirmada.","parentEquipmentId":"SV1801B","parentEquipmentGuid":"206t194YPQWO6Wa6jSddOs","isAssemblyIdentityCarrier":false,"sourceFaceRange":[776,788],"sourceCurrentFaceIndices":[776,777,778,779,780,781,782,783,784,785,786,787],"sourceMeshSha256":"7b60c904c9d84d22fded9be34af09a09a9c198ec8e75e61902634d5e4064c761","sourceVertexIndices":[392,393,394,395,396,397,398,399],"separationMethod":"Partición exacta de triángulos existentes; coordenadas y orientación de caras conservadas.","quantityUse":"Magnitudes geométricas del subvolumen; no son cantidades netas de material, fabricación, suministro o capacidad."} | {"id":"SV1801B","name":"Depósito de nitrógeno líquido SV1801B","relationship":"decomposed_component","parentShapeMeaning":"La forma del objeto que conserva el ID del equipo es únicamente su componente principal; el conjunto completo requiere sus hijos."} | {"kind":"through_parent","parentEquipmentId":"SV1801B","directAnchorageVerified":false,"note":"La relación del conjunto con cimentaciones se conserva en el objeto que mantiene el ID del equipo; no se atribuye fijación directa a cada subcomponente."} | Documento de implantación y apoyo del conjunto padre; no acredita fijación individual de este componente. | SV1801B--support-02 | Envolvente de apoyo 2 · huella real en planta | Equipos | unknown | equipment_dark_frame | {"documentId":"EQ-IMPLANTACION-20260430","title":"Plano del fabricante: implantación de equipos","sheet":"LHD2609-GD01000 · espacio modelo","date":"2026-04-30","componentSourceHandles":["69ABD"]} | Submalla de triángulos existentes; no hay nueva posición ni nuevas caras. | Cotas globales del conjunto conservadas aparte; las dimensiones de esta ficha son de la submalla. | Coordinación del conjunto padre; anclaje directo individual no acreditado. | Superficie y volumen geométricos brutos; no constituyen cantidades netas de obra, material o fabricación. | Plano general y dimensiones globales de SV1801B; no se asignan esas dimensiones globales a este componente. | ["69ABD"] | 1 | no | Submalla exacta; interpretación funcional y cotas parciales provisionales.
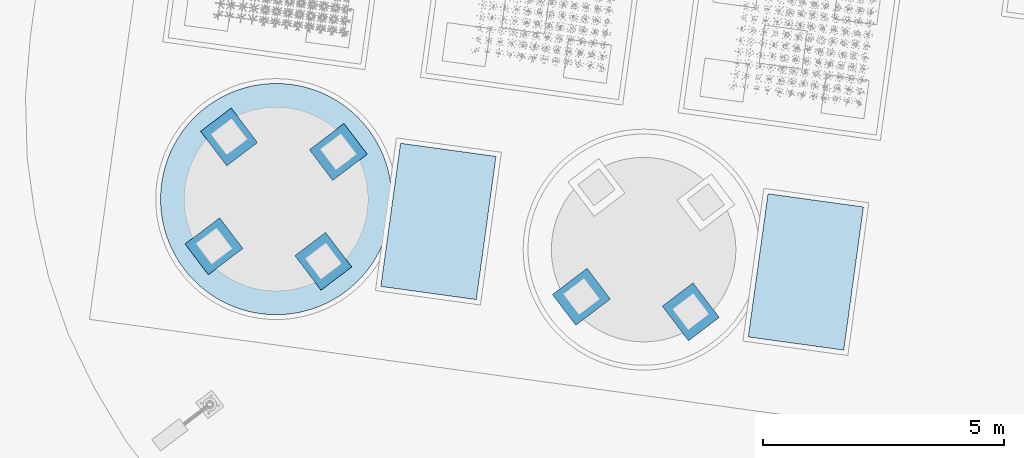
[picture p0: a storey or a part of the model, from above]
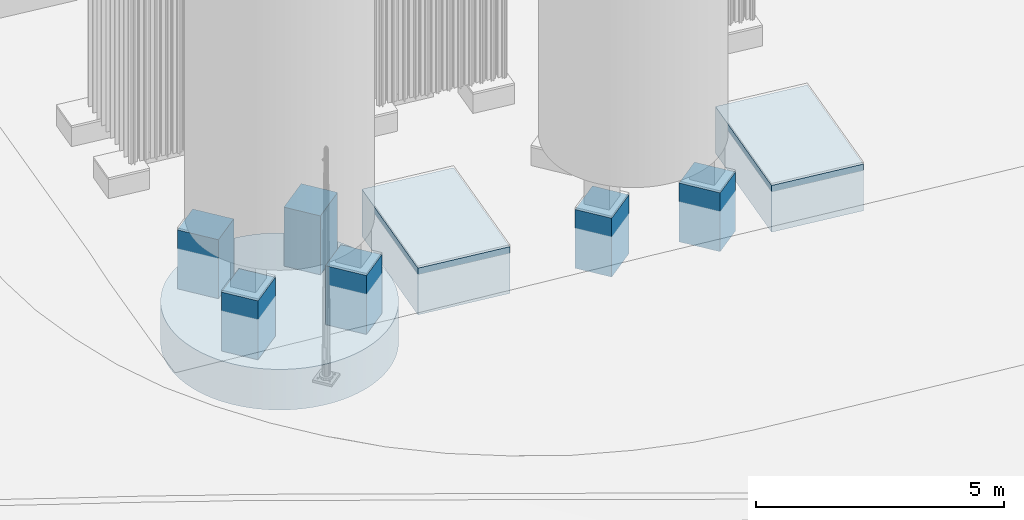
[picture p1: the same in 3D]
Properties of the parts of a building model (IFC4), part 24 of 134

# IfcBuildingElementProxy (140)
Name | Description | Document | Extensión de la malla en X (m) = ExtensionX (m) | Extensión de la malla en Y (m) = ExtensionY (m) | Extensión de la malla en Z (m) = ExtensionZ (m) | Cota inferior de visualización (m) | Cota superior de visualización (m) | SuperficieDeLaMalla (m2) | VolumenGeometrico (m3) | level | category = Categoria = Funcion | representationKind | material | dimensions | JH_InformacionBIM, source = DocumentoFuente | positioning = PosicionYEstado | issues | detailGeometry | geometryMetrics | installationSource | layerId = IdentificadorCapa | visualLayer | materialAppearance | componentSeparation | visualizationIdentity | classification | appearance | Disciplina | Material | Capa BIM = NombreCapa | Acabado de visualización = Acabado | Estado del acabado = Estado | Identificador | JH_Trazabilidad, IncidenciasPendientes | UsoDeLasMagnitudes | JH_EvidenciaDeMaterial, source | JH_DetalleGeometrico, source | VisibilidadInicial | Perfil | ColorRGB | Rugosidad | Metallicidad | Referencia | Nota | Group | parentEquipmentId = Identificador del equipo padre | parentEquipmentName = Equipo padre | parentEquipmentIfcClass | parentEquipmentDimensions | parentEquipmentPositioning | parentEquipmentIssues | parentEquipmentDetail | componentRole = Rol del componente | assemblyBBox | assemblyGeometryMetrics | manufacturerDetailsPending | component | assembly | foundationRelationship | installationSourceScope | Identificador del elemento = sourcePartId | Componente | Capa de visualización | Estado del material | Perfil visual del material | Fuente del componente | Criterio de partición | Criterio de las dimensiones | Relación con cimentaciones | Aplicabilidad de las mediciones | Referencia dimensional del conjunto | sourceHandles | partCount | partsAreBOM | status
Compresor de aire AC1001A · Carcasa principal · región CAD 2 | Componente de equipo · envolvente exterior | Plano del fabricante: implantación de equipos · referencia E7 | 0.964653 | 2.19971 | 2.3 | 286.65 | 288.95 | 16.2024 | 3.29986 | Apoyo relativo +0.400 m; cero absoluto provisional | Componente de equipo · envolvente exterior | equipmentComponent | {"name":"No especificado","source":"Sin especificación de material en la documentación revisada","status":"unknown"} | {"documented":[{"label":"Referencia dimensional del conjunto","value":"Plano general y dimensiones globales de AC1001A; no se asignan esas dimensiones globales a este componente.","unit":"","source":"EQ-IMPLANTACION-20260430 · LHD2609-GD01000 · espacio modelo","status":"referencia_del_conjunto"}],"geometry":[{"label":"Extensión de la malla en X","value":0.9646529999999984,"unit":"m","source":"Geometría releída del IFC; datum absoluto de proceso provisional","status":"derivado"},{"label":"Extensión de la malla en Y","value":2.199714,"unit":"m","source":"Geometría releída del IFC; datum absoluto de proceso provisional","status":"derivado"},{"label":"Extensión de la malla en Z","value":2.3000000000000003,"unit":"m","source":"Geometría releída del IFC; datum absoluto de proceso provisional","status":"derivado"},{"label":"Cota inferior de visualización","value":286.65,"unit":"m","source":"Geometría releída del IFC; datum absoluto de proceso provisional","status":"derivado"},{"label":"Cota superior de visualización","value":288.95,"unit":"m","source":"Geometría releída del IFC; datum absoluto de proceso provisional","status":"derivado"}],"notes":["Las dimensiones del equipo completo se conservan en parentEquipmentDimensions.","Las extensiones en X/Y son de los ejes del modelo y no sustituyen cotas locales de fabricación.","No se infieren espesores de chapa, tolerancias ni dimensiones de piezas a partir de la partición."]} | {"documentId":"EQ-IMPLANTACION-20260430","title":"Plano del fabricante: implantación de equipos","sheet":"LHD2609-GD01000 · espacio modelo","date":"2026-04-30","componentSourceHandles":["7133E","7133F","732E7","73405","73406","73408","73409","73441"]} | {"horizontalStatus":"derivado_del_conjunto","verticalStatus":"derivado_del_conjunto","coordinateSystem":"model_local_m","parentEquipmentId":"AC1001A","transformApplied":false,"note":"Coordenadas copiadas exactamente del equipo coordinado; no se ha movido, girado, elevado ni reescalado este componente.","foundationRelationship":"El apoyo y las cotas de instalación se documentan para el conjunto padre. Esta submalla no acredita un anclaje directo.","meshMinimumAbsoluteElevationM":286.65,"assemblyPlacementField":"parentEquipmentPositioning"} | ["Componente separado de una reconstrucción documental del conjunto. Las alturas y detalles parciales conservan las limitaciones del fabricante registradas en parentEquipmentIssues.","Esta representación exterior no crea una chapa hueca ni añade componentes internos no documentados.","La pertenencia al conjunto no demuestra apoyo o anclaje directo a la cimentación."] | {"source":{"documentId":"EQ-IMPLANTACION-20260430","title":"Plano del fabricante: implantación de equipos","sheet":"LHD2609-GD01000 · espacio modelo","date":"2026-04-30","componentSourceHandles":["7133E","7133F","732E7","73405","73406","73408","73409","73441"]},"sourcePartId":"AC1001A--cad-region-002","sourceHandles":["7133E","7133F","732E7","73405","73406","73408","73409","73441"],"partCount":1,"partsAreBOM":false,"status":"Submalla exacta; interpretación funcional y cotas parciales provisionales."} | {"boundingBoxM":{"min":[49.234108,71.029928,1.65],"max":[50.198761,73.229642,3.95]},"extentsM":[0.964653,2.199714,2.3],"meshSurfaceM2":16.202434,"meshVolumeM3":3.29986,"closedSolid":true,"basis":"Geometría de coordinación. Los volúmenes de referencia y subcomponentes no son cantidades de material ni componentes de fabricación certificados."} | {"documentId":"LHD2609-JG00100-20260904","title":"Cimentaciones y pedestales de equipos · revisión recibida 04/09/2026","date":"2026-09-04","sheet":"1 / 1-1","sourceHandles":["28C35","28C38","28C3B","28C89"]} | equipment_enclosures | {"id":"equipment_enclosures","name":"Envolventes de equipos"} | {"profileId":"equipment_light_gray","name":"Equipo · gris claro provisional","materialName":"No especificado","physicalMaterialStatus":"unknown","physicalMaterialSource":"Sin especificación de material en la documentación revisada","appearanceStatus":"provisional","appearanceBasis":"Referencia visual de fotografías públicas de Jinhong Gas / fabricante. Apariencia provisional para coordinación; fotografías oficiales pueden orientar el color, pero no acreditan el material, el acabado ni el equipo concreto.","appearanceReferences":["jinhong-official-asu"],"note":"El perfil visual no confirma material, grado ni acabado del componente."} | {"status":"componente_independiente","note":"Objeto independiente seleccionable. Las caras se asignan una sola vez entre todos los componentes del conjunto.","parentEquipmentId":"AC1001A","isAssemblyIdentityCarrier":false} | {"elementId":"AC1001A--cad-region-002","ifcGuid":"2ihgK8Zj1G3g7nsLFYYnQK","ifcClass":"IfcBuildingElementProxy","buildingId":"process_plant","buildingName":"Planta de proceso","sourceDocumentId":"EQ-IMPLANTACION-20260430","sourceRepresentationKind":"equipmentComponent"} | {"layerId":"equipment_enclosures","layerName":"Envolventes de equipos","role":"Componente de equipo · envolvente exterior","basis":"Clasificación por función del elemento; no modifica las especificaciones documentales."} | {"profileId":"equipment_light_gray","name":"Equipo · gris claro provisional","status":"provisional","basis":"Referencia visual de fotografías públicas de Jinhong Gas / fabricante. Apariencia provisional para coordinación; fotografías oficiales pueden orientar el color, pero no acreditan el material, el acabado ni el equipo concreto.","physicalMaterialUnchanged":true} | Envolventes de equipos | No especificado | Envolventes de equipos | Equipo · gris claro provisional | provisional | AC1001A--cad-region-002 | ["Componente separado de una reconstrucción documental del conjunto. Las alturas y detalles parciales conservan las limitaciones del fabricante registradas en parentEquipmentIssues.","Esta representación exterior no crea una chapa hueca ni añade componentes internos no documentados.","La pertenencia al conjunto no demuestra apoyo o anclaje directo a la cimentación."] | Geometría de coordinación. Los volúmenes de referencia y subcomponentes no son cantidades de material ni componentes de fabricación certificados. | Sin especificación de material en la documentación revisada | {"documentId":"EQ-IMPLANTACION-20260430","title":"Plano del fabricante: implantación de equipos","sheet":"LHD2609-GD01000 · espacio modelo","date":"2026-04-30","componentSourceHandles":["7133E","7133F","732E7","73405","73406","73408","73409","73441"]} | yes | equipment_light_gray | [0.88,0.89,0.88] | 0.45 | 0.28 | Referencia visual de fotografías públicas de Jinhong Gas / fabricante. Apariencia provisional para coordinación; fotografías oficiales pueden orientar el color, pero no acreditan el material, el acabado ni el equipo concreto. | La apariencia no certifica el material físico ni el acabado de fabricación. | BIM · Envolventes de equipos | AC1001A | Compresor de aire AC1001A | IfcCompressor | {"documented":[{"label":"Dimensión X local del bastidor de referencia CAD","value":2.35,"unit":"m","source":"EQ-CARGAS-20260825 · contorno CAD · handles 3F3","status":"derivado"},{"label":"Dimensión Y local del bastidor de referencia CAD","value":5.22,"unit":"m","source":"EQ-CARGAS-20260825 · contorno CAD · handles 3F3","status":"derivado"},{"label":"Altura acotada","value":3.38,"unit":"m","source":"EQ-CARGAS-20260825 · handle 52E","status":"documentado"},{"label":"Cota relativa de la superficie de apoyo","value":0.4,"unit":"m","source":"LHD2609-JG00100-20260904 · sección 1 / 1-1 · 28C35, 28C38, 28C3B, 28C89","status":"documentado"}],"geometry":[{"label":"Extensión de la malla en X","value":3.1775829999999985,"unit":"m","source":"Geometría releída del IFC; datum absoluto de proceso provisional","status":"derivado"},{"label":"Extensión de la malla en Y","value":6.404527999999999,"unit":"m","source":"Geometría releída del IFC; datum absoluto de proceso provisional","status":"derivado"},{"label":"Extensión de la malla en Z","value":3.3800000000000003,"unit":"m","source":"Geometría releída del IFC; datum absoluto de proceso provisional","status":"derivado"},{"label":"Cota inferior de visualización","value":286.5,"unit":"m","source":"Geometría releída del IFC; datum absoluto de proceso provisional","status":"derivado"},{"label":"Cota superior de visualización","value":289.88,"unit":"m","source":"Geometría releída del IFC; datum absoluto de proceso provisional","status":"derivado"}],"notes":["Las extensiones de la malla se miden en los ejes del proyecto tras el giro de implantación; no sustituyen las dimensiones locales del fabricante.","La envolvente, su volumen y los espesores de visualización no son volúmenes de material ni cantidades de compra, construcción o fabricación.","Las dimensiones documentadas distinguen cotas explícitas y medidas extraídas de contornos CAD; las dimensiones geométricas describen únicamente la malla publicada.","Las extensiones de la malla refinada y las dimensiones documentadas del contorno o bastidor tienen distinto alcance; las cotas parciales del detalle son provisionales."]} | {"Estado de la planta":"Derivado del CAD y del giro de implantación","Nivel relativo del apoyo (m)":0.4,"Estado del nivel relativo":"Documentado en el plano de cimentaciones","Cero absoluto de visualización (m)":286.1,"Estado del cero absoluto":"Provisional","Cota del apoyo de visualización (m)":286.5,"Desplazamiento aplicado a la malla (m)":0.40000000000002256,"Criterio":"Nivel de apoyo relativo documentado. Se adopta el cero de proceso a 286,10 m solo para visualización; la equivalencia absoluta no está confirmada. No se añade un espesor de montaje sin cota del fabricante."} | ["La máquina está contenida en la envolvente de la cabina acústica; su superposición no acredita una interferencia física.","El bastidor CAD coincide con la referencia de 2,35 × 5,22 m del plano de cargas, pero cuerpos y auxiliares del detalle de abril sobresalen de esa referencia, hasta aproximadamente 1,048 m por el extremo sur y 0,246 m por el lado oeste. Extensión geométrica resultante: 2,595899 × 6,268101 × 3,38 m, derivada y pendiente de coordinación entre revisiones. Permanecen dentro de la cabina acústica. Compatibilidad de revisión pendiente de fabricante.","Todas las alturas parciales son hipótesis de visualización; solo la altura total de 3,38 m está acotada.","Las regiones del dibujo se usan como envolventes de cuerpos; la identificación funcional y la cota Z de cada pieza requieren verificación.","Pequeños taladros, tornillería y detalles interiores de las regiones no se extruyen como vacíos de fabricación.","El bastidor documentado mide 2,35 × 5,22 m. Los accesorios del detalle de abril sobresalen; el conjunto refinado ocupa aproximadamente 2,596 × 6,268 m en ejes del fabricante, pendiente de coordinación entre revisiones.","El acabado de grout HA-35 de 50 mm termina en +0,400; el hormigón termina en +0,350. La losa MAC contigua termina en +0,200.","El cero absoluto de la revisión no está definido; 286,10 m sigue siendo una hipótesis de coordinación.","Se alinea el punto inferior del conjunto del equipo, incluidos los pies ya representados, con la superficie de apoyo terminada; no se añade un espesor de calzos, placa o grout del fabricante no documentado."] | {"revision":"Detalle en planta de 2026-04-30 coordinado de forma preliminar con envolventes y alturas de 2026-08-25","status":"provisional","verticalRule":"Altura total documentada: 3,38 m. Plataforma gráfica de 0,15 m; los cuerpos extraídos de la planta reciben alturas provisionales entre 1,00 y 3,38 m, detalladas por subvolumen. No se dispone de alzado acotado de cada componente.","partCount":26,"source":{"documentId":"EQ-IMPLANTACION-20260430","title":"Plano del fabricante: implantación de equipos","sheet":"LHD2609-GD01000 · espacio modelo","date":"2026-04-30"},"heightSource":{"documentId":"EQ-CARGAS-20260825","title":"Plano del fabricante: cargas de equipos","sheet":"Espacio modelo","date":"2026-08-25"},"unconfirmedDimensions":["Todas las alturas parciales son hipótesis de visualización; solo la altura total de 3,38 m está acotada.","Las regiones del dibujo se usan como envolventes de cuerpos; la identificación funcional y la cota Z de cada pieza requieren verificación.","Pequeños taladros, tornillería y detalles interiores de las regiones no se extruyen como vacíos de fabricación."],"quantityUse":"Magnitudes de la geometría representada; no son cantidades de material, obra, compra, capacidad útil ni fabricación. En geometrías compuestas se suman superficies y volúmenes de partes y pueden existir solapes no depurados.","partsAreBOM":false} | provisional_casing_region | {"min":[48.139687,70.121823,1.5],"max":[51.31727,76.526351,4.88]} | {"boundingBoxM":{"min":[48.139687,70.121823,1.5],"max":[51.31727,76.526351,4.88]},"extentsM":[3.1775829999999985,6.404527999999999,3.38],"meshSurfaceM2":165.1982435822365,"meshVolumeM3":20.17009895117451,"closedSolid":true,"windingConsistent":true,"basis":"Submalla exacta de los triángulos del modelo IFC coordinado; separación de componentes sin transformación ni retesselación."} | ["Todas las alturas parciales son hipótesis de visualización; solo la altura total de 3,38 m está acotada.","Las regiones del dibujo se usan como envolventes de cuerpos; la identificación funcional y la cota Z de cada pieza requieren verificación.","Pequeños taladros, tornillería y detalles interiores de las regiones no se extruyen como vacíos de fabricación.","La separación gráfica no aporta cotas de fabricación ni identifica piezas internas no documentadas.","Los materiales y acabados permanecen provisionales; las fotografías públicas solo orientan la apariencia."] | {"id":"AC1001A--cad-region-002","sourcePartId":"AC1001A--cad-region-002","name":"Carcasa principal · región CAD 2","role":"provisional_casing_region","classificationStatus":"provisional","classificationBasis":"Rol del subvolumen gráfico según el activo de detalle; identidad de fabricación no confirmada.","parentEquipmentId":"AC1001A","parentEquipmentGuid":"1ZhOcwnsbMzxhqtlvKa3pG","isAssemblyIdentityCarrier":false,"sourceFaceRange":[36,68],"sourceCurrentFaceIndices":[36,37,38,39,40,41,42,43,44,45,46,47,48,49,50,51,52,53,54,55,56,57,58,59,60,61,62,63,64,65,66,67],"sourceMeshSha256":"7b60c904c9d84d22fded9be34af09a09a9c198ec8e75e61902634d5e4064c761","sourceVertexIndices":[22,23,24,25,26,27,28,29,30,31,32,33,34,35,36,37,38,39],"separationMethod":"Partición exacta de triángulos existentes; coordenadas y orientación de caras conservadas.","quantityUse":"Magnitudes geométricas del subvolumen; no son cantidades netas de material, fabricación, suministro o capacidad."} | {"id":"AC1001A","name":"Compresor de aire AC1001A","relationship":"decomposed_component","parentShapeMeaning":"La forma del objeto que conserva el ID del equipo es únicamente su componente principal; el conjunto completo requiere sus hijos."} | {"kind":"through_parent","parentEquipmentId":"AC1001A","directAnchorageVerified":false,"note":"La relación del conjunto con cimentaciones se conserva en el objeto que mantiene el ID del equipo; no se atribuye fijación directa a cada subcomponente."} | Documento de implantación y apoyo del conjunto padre; no acredita fijación individual de este componente. | AC1001A--cad-region-002 | Carcasa principal · región CAD 2 | Envolventes de equipos | unknown | equipment_light_gray | {"documentId":"EQ-IMPLANTACION-20260430","title":"Plano del fabricante: implantación de equipos","sheet":"LHD2609-GD01000 · espacio modelo","date":"2026-04-30","componentSourceHandles":["7133E","7133F","732E7","73405","73406","73408","73409","73441"]} | Submalla de triángulos existentes; no hay nueva posición ni nuevas caras. | Cotas globales del conjunto conservadas aparte; las dimensiones de esta ficha son de la submalla. | Coordinación del conjunto padre; anclaje directo individual no acreditado. | Superficie y volumen geométricos brutos; no constituyen cantidades netas de obra, material o fabricación. | Plano general y dimensiones globales de AC1001A; no se asignan esas dimensiones globales a este componente. | ["7133E","7133F","732E7","73405","73406","73408","73409","73441"] | 1 | no | Submalla exacta; interpretación funcional y cotas parciales provisionales.
Compresor de aire AC1001A · Cuerpo de equipo · región CAD 3 | Componente de equipo · cuerpo o accesorio | Plano del fabricante: implantación de equipos · referencia E7 | 2.34072 | 1.14581 | 3.23 | 286.65 | 289.88 | 23.8446 | 6.15491 | Apoyo relativo +0.400 m; cero absoluto provisional | Componente de equipo · cuerpo o accesorio | equipmentComponent | {"name":"No especificado","source":"Sin especificación de material en la documentación revisada","status":"unknown"} | {"documented":[{"label":"Referencia dimensional del conjunto","value":"Plano general y dimensiones globales de AC1001A; no se asignan esas dimensiones globales a este componente.","unit":"","source":"EQ-IMPLANTACION-20260430 · LHD2609-GD01000 · espacio modelo","status":"referencia_del_conjunto"}],"geometry":[{"label":"Extensión de la malla en X","value":2.340715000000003,"unit":"m","source":"Geometría releída del IFC; datum absoluto de proceso provisional","status":"derivado"},{"label":"Extensión de la malla en Y","value":1.1458139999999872,"unit":"m","source":"Geometría releída del IFC; datum absoluto de proceso provisional","status":"derivado"},{"label":"Extensión de la malla en Z","value":3.23,"unit":"m","source":"Geometría releída del IFC; datum absoluto de proceso provisional","status":"derivado"},{"label":"Cota inferior de visualización","value":286.65,"unit":"m","source":"Geometría releída del IFC; datum absoluto de proceso provisional","status":"derivado"},{"label":"Cota superior de visualización","value":289.88,"unit":"m","source":"Geometría releída del IFC; datum absoluto de proceso provisional","status":"derivado"}],"notes":["Las dimensiones del equipo completo se conservan en parentEquipmentDimensions.","Las extensiones en X/Y son de los ejes del modelo y no sustituyen cotas locales de fabricación.","No se infieren espesores de chapa, tolerancias ni dimensiones de piezas a partir de la partición."]} | {"documentId":"EQ-IMPLANTACION-20260430","title":"Plano del fabricante: implantación de equipos","sheet":"LHD2609-GD01000 · espacio modelo","date":"2026-04-30","componentSourceHandles":["71316","71317","72C0A","72C15","72C2A","72C3B","72C3F","72C41","72C42","72C44","72C45","72C46","72C47","72C48","72C49","72C4A","72C4B","72C4C","72C4D","72C4E","72C4F","72C50","72C51","72C52","72C53","72C54","72C55","72C56","72C57","72C58","72C59","72C5A","72C5B","72C5C","72C5D","72C5E","72C5F","72C60","72C61","72C62","72C63","72C64","72C65","72C66","72C67","72C68","72C69","72C6A","72C6B","72C6C","72C6D","72C6E","72C6F","72C70","72C71","72C72","72C73","72C74","72C75","72C76","72C77","72C78","72C79","72C7A","72C7B","72C7C","72C7D","72C7E","72C7F","72C80","72C84","72C88","72C89","72C9E","72CA1","72CA4","72CA7","72CAA","72CAD","72CB0","72CB3","72CB6","72CB9","72CBC","72CBF","72CC2","72CC5","72CC8","72CCB","72CCE","72CD1","72CD4","72CD7","72CDA","72CDC","72CDD","72CE5","72CE6","72CE7","72CE8","72CE9","72CEA","72CEB","72CEC","72CED","72CEE","72CEF","72CF0","72CF1","72CF2","72CF3","72CF4","72CF5","72CF6","72CF7","72CF8","72CF9","72CFA","72CFB","72CFC","72CFD","72CFE","72CFF","72D00","72D01","72D02","72D03","72D04","72D05","72D06","72D07","72D08","72D0A","72D0B","72D0C","72D0D","72D0E","72D0F","72D10","72D11","72D13","72D14","72D15","72D16","72D17","72D18","72D19","72D1A","72D1B","72D1C","72D1D","72D1E","72D1F","72D20","72D21","72D22","72D23","72D24","72D26","72D27","72D28","72D29","72D2A","72D2B","72D2C","72D2D","72D2E","72D31","72D33","72D51","72D52","72D65","72D66","72D67","72D68","72D69","72D6A","72D6B","72D6C","72D6D","72D6E","72D6F","72D70","72D71","72D72","72D73","72D74","72D75","72D76","72D77","72D78","72D79","72D7A","72D7B","72D7C","72D7D","72D7E","72D7F","72D80","72D81","72D82","72D83","72D84","72D85","72D86","72D87","72D88","72D89","72D8A","72D8B","72D8C","72D8D","72D8E","72D8F","72D90","72D91","72D92","72D93","72D94","72D95","72D96","72D97","72D98","72D99","72D9A","72D9B","72D9C","72D9D","72D9E","72D9F","72DA0","72DA1","72DA2","72DA3","72DA4","72DA5","72DA6","72DA7","72DA8","72DA9","72DAA","72DAB","72DAC","72DAD","72DAE","72DAF","72DB0","72DB1","72DB2","72DB3","72DB4","72DB5","72DB6","72DB7","72DB8","72DB9","72DBA","72DBB","72DBC","72DBD","72DBE","72DBF","72DC0","72DC1","72DC2","72DC3","72DC4","72DC5","72DC6","72DC7","72DC8","72DC9","72DCA","72DCB","72DCC","72DCD","72DCE","72DCF","72DD0","72DD1","72DD2","72DD3","72DD4","72DD5","72DD6","72DD7","72DD8","72DD9","72DDA","72DDB","72DDC","72DDD","72DDE","72DDF","72DE0","72DE1","72DE2","72DE3","72DE4","72DE5","72DE6","72DE7","72DE8","72DE9","72DEA","72DEB","72DEC","72DED","72DEE","72DEF","72DF0","72DF1","72DF2","72DF3","72DF4","72DF5","72DF6","72DF7","72DF8","72DF9","72DFA","72DFB","72DFC","72DFD","72DFE","72DFF","72E00","72E01","72E02","72E03","72E04","72E05","72E06","72E07","72E08","72E09","72E0A","72E0B","72E0C","72E0D","72E0E","72E0F","72E10","72E11","72E12","72E13","72E14","72E15","72E16","72E17","72E18","72E19","72E1A","72E1B","72E1C","72E1D","72E1E","72E1F","72E20","72E21","72E22","72E23","72E24","72E25","72E26","72E27","72E28","72E29","72E2A","72E2B","72E2C","72E2D","72E2E","72E2F","72E30","72E31","72E32","72E33","72E34","72E35","72E36","72E37","72E38","72E39","72E3A","72E3B","72E3C","72E3D","72E3E","72E3F","72E40","72E41","72E42","72E43","72E44","72E45","72E46","72E47","72E48","72E49","72E4A","72E4B","72E4C","72E4D","72E4E","72E4F","72E50","72E51","72E52","72E53","72E54","72E55","72E56","72E57","72E58","72E59","72E5A","72E5B","72E5C","72E5D","72E5E","72E5F","72E60","72E61","72E62","72E63","72E64","72E65","72E66","72E67","72E68","72E69","72E6A","72E6B","72E6C","72E6D","72E6E","72E6F","72E70","72E71","72E72","72E73","72E74","72E75","72E76","72E77","72E78","72E79","72E7A","72E7B","72E7E","72E7F","72E85","72E86","72E87","72E88","72E8D","72E8E","72E8F","72E90","72E92","72E93","72E99","72EBB","72EBC","72EBD","72EBE","72EBF","72EC0","72EC1","72EC2","72EC4","72EC5","72EC6","72EC7","72EC8","72EC9","72ECA","72ECB","72ECC","72ECD","72ECE","72ED0","72ED1","72ED2","72ED3","72ED4","72ED5","72ED6","72ED7","72ED8","72ED9","72EDA","72F07","72F08","72F09","72F0A","72F0C"]} | {"horizontalStatus":"derivado_del_conjunto","verticalStatus":"derivado_del_conjunto","coordinateSystem":"model_local_m","parentEquipmentId":"AC1001A","transformApplied":false,"note":"Coordenadas copiadas exactamente del equipo coordinado; no se ha movido, girado, elevado ni reescalado este componente.","foundationRelationship":"El apoyo y las cotas de instalación se documentan para el conjunto padre. Esta submalla no acredita un anclaje directo.","meshMinimumAbsoluteElevationM":286.65,"assemblyPlacementField":"parentEquipmentPositioning"} | ["Componente separado de una reconstrucción documental del conjunto. Las alturas y detalles parciales conservan las limitaciones del fabricante registradas en parentEquipmentIssues.","Esta representación exterior no crea una chapa hueca ni añade componentes internos no documentados.","La pertenencia al conjunto no demuestra apoyo o anclaje directo a la cimentación."] | {"source":{"documentId":"EQ-IMPLANTACION-20260430","title":"Plano del fabricante: implantación de equipos","sheet":"LHD2609-GD01000 · espacio modelo","date":"2026-04-30","componentSourceHandles":["71316","71317","72C0A","72C15","72C2A","72C3B","72C3F","72C41","72C42","72C44","72C45","72C46","72C47","72C48","72C49","72C4A","72C4B","72C4C","72C4D","72C4E","72C4F","72C50","72C51","72C52","72C53","72C54","72C55","72C56","72C57","72C58","72C59","72C5A","72C5B","72C5C","72C5D","72C5E","72C5F","72C60","72C61","72C62","72C63","72C64","72C65","72C66","72C67","72C68","72C69","72C6A","72C6B","72C6C","72C6D","72C6E","72C6F","72C70","72C71","72C72","72C73","72C74","72C75","72C76","72C77","72C78","72C79","72C7A","72C7B","72C7C","72C7D","72C7E","72C7F","72C80","72C84","72C88","72C89","72C9E","72CA1","72CA4","72CA7","72CAA","72CAD","72CB0","72CB3","72CB6","72CB9","72CBC","72CBF","72CC2","72CC5","72CC8","72CCB","72CCE","72CD1","72CD4","72CD7","72CDA","72CDC","72CDD","72CE5","72CE6","72CE7","72CE8","72CE9","72CEA","72CEB","72CEC","72CED","72CEE","72CEF","72CF0","72CF1","72CF2","72CF3","72CF4","72CF5","72CF6","72CF7","72CF8","72CF9","72CFA","72CFB","72CFC","72CFD","72CFE","72CFF","72D00","72D01","72D02","72D03","72D04","72D05","72D06","72D07","72D08","72D0A","72D0B","72D0C","72D0D","72D0E","72D0F","72D10","72D11","72D13","72D14","72D15","72D16","72D17","72D18","72D19","72D1A","72D1B","72D1C","72D1D","72D1E","72D1F","72D20","72D21","72D22","72D23","72D24","72D26","72D27","72D28","72D29","72D2A","72D2B","72D2C","72D2D","72D2E","72D31","72D33","72D51","72D52","72D65","72D66","72D67","72D68","72D69","72D6A","72D6B","72D6C","72D6D","72D6E","72D6F","72D70","72D71","72D72","72D73","72D74","72D75","72D76","72D77","72D78","72D79","72D7A","72D7B","72D7C","72D7D","72D7E","72D7F","72D80","72D81","72D82","72D83","72D84","72D85","72D86","72D87","72D88","72D89","72D8A","72D8B","72D8C","72D8D","72D8E","72D8F","72D90","72D91","72D92","72D93","72D94","72D95","72D96","72D97","72D98","72D99","72D9A","72D9B","72D9C","72D9D","72D9E","72D9F","72DA0","72DA1","72DA2","72DA3","72DA4","72DA5","72DA6","72DA7","72DA8","72DA9","72DAA","72DAB","72DAC","72DAD","72DAE","72DAF","72DB0","72DB1","72DB2","72DB3","72DB4","72DB5","72DB6","72DB7","72DB8","72DB9","72DBA","72DBB","72DBC","72DBD","72DBE","72DBF","72DC0","72DC1","72DC2","72DC3","72DC4","72DC5","72DC6","72DC7","72DC8","72DC9","72DCA","72DCB","72DCC","72DCD","72DCE","72DCF","72DD0","72DD1","72DD2","72DD3","72DD4","72DD5","72DD6","72DD7","72DD8","72DD9","72DDA","72DDB","72DDC","72DDD","72DDE","72DDF","72DE0","72DE1","72DE2","72DE3","72DE4","72DE5","72DE6","72DE7","72DE8","72DE9","72DEA","72DEB","72DEC","72DED","72DEE","72DEF","72DF0","72DF1","72DF2","72DF3","72DF4","72DF5","72DF6","72DF7","72DF8","72DF9","72DFA","72DFB","72DFC","72DFD","72DFE","72DFF","72E00","72E01","72E02","72E03","72E04","72E05","72E06","72E07","72E08","72E09","72E0A","72E0B","72E0C","72E0D","72E0E","72E0F","72E10","72E11","72E12","72E13","72E14","72E15","72E16","72E17","72E18","72E19","72E1A","72E1B","72E1C","72E1D","72E1E","72E1F","72E20","72E21","72E22","72E23","72E24","72E25","72E26","72E27","72E28","72E29","72E2A","72E2B","72E2C","72E2D","72E2E","72E2F","72E30","72E31","72E32","72E33","72E34","72E35","72E36","72E37","72E38","72E39","72E3A","72E3B","72E3C","72E3D","72E3E","72E3F","72E40","72E41","72E42","72E43","72E44","72E45","72E46","72E47","72E48","72E49","72E4A","72E4B","72E4C","72E4D","72E4E","72E4F","72E50","72E51","72E52","72E53","72E54","72E55","72E56","72E57","72E58","72E59","72E5A","72E5B","72E5C","72E5D","72E5E","72E5F","72E60","72E61","72E62","72E63","72E64","72E65","72E66","72E67","72E68","72E69","72E6A","72E6B","72E6C","72E6D","72E6E","72E6F","72E70","72E71","72E72","72E73","72E74","72E75","72E76","72E77","72E78","72E79","72E7A","72E7B","72E7E","72E7F","72E85","72E86","72E87","72E88","72E8D","72E8E","72E8F","72E90","72E92","72E93","72E99","72EBB","72EBC","72EBD","72EBE","72EBF","72EC0","72EC1","72EC2","72EC4","72EC5","72EC6","72EC7","72EC8","72EC9","72ECA","72ECB","72ECC","72ECD","72ECE","72ED0","72ED1","72ED2","72ED3","72ED4","72ED5","72ED6","72ED7","72ED8","72ED9","72EDA","72F07","72F08","72F09","72F0A","72F0C"]},"sourcePartId":"AC1001A--cad-region-003","sourceHandles":["71316","71317","72C0A","72C15","72C2A","72C3B","72C3F","72C41","72C42","72C44","72C45","72C46","72C47","72C48","72C49","72C4A","72C4B","72C4C","72C4D","72C4E","72C4F","72C50","72C51","72C52","72C53","72C54","72C55","72C56","72C57","72C58","72C59","72C5A","72C5B","72C5C","72C5D","72C5E","72C5F","72C60","72C61","72C62","72C63","72C64","72C65","72C66","72C67","72C68","72C69","72C6A","72C6B","72C6C","72C6D","72C6E","72C6F","72C70","72C71","72C72","72C73","72C74","72C75","72C76","72C77","72C78","72C79","72C7A","72C7B","72C7C","72C7D","72C7E","72C7F","72C80","72C84","72C88","72C89","72C9E","72CA1","72CA4","72CA7","72CAA","72CAD","72CB0","72CB3","72CB6","72CB9","72CBC","72CBF","72CC2","72CC5","72CC8","72CCB","72CCE","72CD1","72CD4","72CD7","72CDA","72CDC","72CDD","72CE5","72CE6","72CE7","72CE8","72CE9","72CEA","72CEB","72CEC","72CED","72CEE","72CEF","72CF0","72CF1","72CF2","72CF3","72CF4","72CF5","72CF6","72CF7","72CF8","72CF9","72CFA","72CFB","72CFC","72CFD","72CFE","72CFF","72D00","72D01","72D02","72D03","72D04","72D05","72D06","72D07","72D08","72D0A","72D0B","72D0C","72D0D","72D0E","72D0F","72D10","72D11","72D13","72D14","72D15","72D16","72D17","72D18","72D19","72D1A","72D1B","72D1C","72D1D","72D1E","72D1F","72D20","72D21","72D22","72D23","72D24","72D26","72D27","72D28","72D29","72D2A","72D2B","72D2C","72D2D","72D2E","72D31","72D33","72D51","72D52","72D65","72D66","72D67","72D68","72D69","72D6A","72D6B","72D6C","72D6D","72D6E","72D6F","72D70","72D71","72D72","72D73","72D74","72D75","72D76","72D77","72D78","72D79","72D7A","72D7B","72D7C","72D7D","72D7E","72D7F","72D80","72D81","72D82","72D83","72D84","72D85","72D86","72D87","72D88","72D89","72D8A","72D8B","72D8C","72D8D","72D8E","72D8F","72D90","72D91","72D92","72D93","72D94","72D95","72D96","72D97","72D98","72D99","72D9A","72D9B","72D9C","72D9D","72D9E","72D9F","72DA0","72DA1","72DA2","72DA3","72DA4","72DA5","72DA6","72DA7","72DA8","72DA9","72DAA","72DAB","72DAC","72DAD","72DAE","72DAF","72DB0","72DB1","72DB2","72DB3","72DB4","72DB5","72DB6","72DB7","72DB8","72DB9","72DBA","72DBB","72DBC","72DBD","72DBE","72DBF","72DC0","72DC1","72DC2","72DC3","72DC4","72DC5","72DC6","72DC7","72DC8","72DC9","72DCA","72DCB","72DCC","72DCD","72DCE","72DCF","72DD0","72DD1","72DD2","72DD3","72DD4","72DD5","72DD6","72DD7","72DD8","72DD9","72DDA","72DDB","72DDC","72DDD","72DDE","72DDF","72DE0","72DE1","72DE2","72DE3","72DE4","72DE5","72DE6","72DE7","72DE8","72DE9","72DEA","72DEB","72DEC","72DED","72DEE","72DEF","72DF0","72DF1","72DF2","72DF3","72DF4","72DF5","72DF6","72DF7","72DF8","72DF9","72DFA","72DFB","72DFC","72DFD","72DFE","72DFF","72E00","72E01","72E02","72E03","72E04","72E05","72E06","72E07","72E08","72E09","72E0A","72E0B","72E0C","72E0D","72E0E","72E0F","72E10","72E11","72E12","72E13","72E14","72E15","72E16","72E17","72E18","72E19","72E1A","72E1B","72E1C","72E1D","72E1E","72E1F","72E20","72E21","72E22","72E23","72E24","72E25","72E26","72E27","72E28","72E29","72E2A","72E2B","72E2C","72E2D","72E2E","72E2F","72E30","72E31","72E32","72E33","72E34","72E35","72E36","72E37","72E38","72E39","72E3A","72E3B","72E3C","72E3D","72E3E","72E3F","72E40","72E41","72E42","72E43","72E44","72E45","72E46","72E47","72E48","72E49","72E4A","72E4B","72E4C","72E4D","72E4E","72E4F","72E50","72E51","72E52","72E53","72E54","72E55","72E56","72E57","72E58","72E59","72E5A","72E5B","72E5C","72E5D","72E5E","72E5F","72E60","72E61","72E62","72E63","72E64","72E65","72E66","72E67","72E68","72E69","72E6A","72E6B","72E6C","72E6D","72E6E","72E6F","72E70","72E71","72E72","72E73","72E74","72E75","72E76","72E77","72E78","72E79","72E7A","72E7B","72E7E","72E7F","72E85","72E86","72E87","72E88","72E8D","72E8E","72E8F","72E90","72E92","72E93","72E99","72EBB","72EBC","72EBD","72EBE","72EBF","72EC0","72EC1","72EC2","72EC4","72EC5","72EC6","72EC7","72EC8","72EC9","72ECA","72ECB","72ECC","72ECD","72ECE","72ED0","72ED1","72ED2","72ED3","72ED4","72ED5","72ED6","72ED7","72ED8","72ED9","72EDA","72F07","72F08","72F09","72F0A","72F0C"],"partCount":1,"partsAreBOM":false,"status":"Submalla exacta; interpretación funcional y cotas parciales provisionales."} | {"boundingBoxM":{"min":[48.917559,75.321306,1.65],"max":[51.258274,76.46712,4.88]},"extentsM":[2.340715,1.145814,3.23],"meshSurfaceM2":23.844592,"meshVolumeM3":6.15491,"closedSolid":true,"basis":"Geometría de coordinación. Los volúmenes de referencia y subcomponentes no son cantidades de material ni componentes de fabricación certificados."} | {"documentId":"LHD2609-JG00100-20260904","title":"Cimentaciones y pedestales de equipos · revisión recibida 04/09/2026","date":"2026-09-04","sheet":"1 / 1-1","sourceHandles":["28C35","28C38","28C3B","28C89"]} | equipment | {"id":"equipment","name":"Equipos"} | {"profileId":"equipment_light_gray","name":"Equipo · gris claro provisional","materialName":"No especificado","physicalMaterialStatus":"unknown","physicalMaterialSource":"Sin especificación de material en la documentación revisada","appearanceStatus":"provisional","appearanceBasis":"Referencia visual de fotografías públicas de Jinhong Gas / fabricante. Apariencia provisional para coordinación; fotografías oficiales pueden orientar el color, pero no acreditan el material, el acabado ni el equipo concreto.","appearanceReferences":["jinhong-official-asu"],"note":"El perfil visual no confirma material, grado ni acabado del componente."} | {"status":"componente_independiente","note":"Objeto independiente seleccionable. Las caras se asignan una sola vez entre todos los componentes del conjunto.","parentEquipmentId":"AC1001A","isAssemblyIdentityCarrier":false} | {"elementId":"AC1001A--cad-region-003","ifcGuid":"3aGTJ5XkzPsOAw6ANh9JON","ifcClass":"IfcBuildingElementProxy","buildingId":"process_plant","buildingName":"Planta de proceso","sourceDocumentId":"EQ-IMPLANTACION-20260430","sourceRepresentationKind":"equipmentComponent"} | {"layerId":"equipment","layerName":"Equipos","role":"Componente de equipo · cuerpo o accesorio","basis":"Clasificación por función del elemento; no modifica las especificaciones documentales."} | {"profileId":"equipment_light_gray","name":"Equipo · gris claro provisional","status":"provisional","basis":"Referencia visual de fotografías públicas de Jinhong Gas / fabricante. Apariencia provisional para coordinación; fotografías oficiales pueden orientar el color, pero no acreditan el material, el acabado ni el equipo concreto.","physicalMaterialUnchanged":true} | Equipos | No especificado | Equipos | Equipo · gris claro provisional | provisional | AC1001A--cad-region-003 | ["Componente separado de una reconstrucción documental del conjunto. Las alturas y detalles parciales conservan las limitaciones del fabricante registradas en parentEquipmentIssues.","Esta representación exterior no crea una chapa hueca ni añade componentes internos no documentados.","La pertenencia al conjunto no demuestra apoyo o anclaje directo a la cimentación."] | Geometría de coordinación. Los volúmenes de referencia y subcomponentes no son cantidades de material ni componentes de fabricación certificados. | Sin especificación de material en la documentación revisada | {"documentId":"EQ-IMPLANTACION-20260430","title":"Plano del fabricante: implantación de equipos","sheet":"LHD2609-GD01000 · espacio modelo","date":"2026-04-30","componentSourceHandles":["71316","71317","72C0A","72C15","72C2A","72C3B","72C3F","72C41","72C42","72C44","72C45","72C46","72C47","72C48","72C49","72C4A","72C4B","72C4C","72C4D","72C4E","72C4F","72C50","72C51","72C52","72C53","72C54","72C55","72C56","72C57","72C58","72C59","72C5A","72C5B","72C5C","72C5D","72C5E","72C5F","72C60","72C61","72C62","72C63","72C64","72C65","72C66","72C67","72C68","72C69","72C6A","72C6B","72C6C","72C6D","72C6E","72C6F","72C70","72C71","72C72","72C73","72C74","72C75","72C76","72C77","72C78","72C79","72C7A","72C7B","72C7C","72C7D","72C7E","72C7F","72C80","72C84","72C88","72C89","72C9E","72CA1","72CA4","72CA7","72CAA","72CAD","72CB0","72CB3","72CB6","72CB9","72CBC","72CBF","72CC2","72CC5","72CC8","72CCB","72CCE","72CD1","72CD4","72CD7","72CDA","72CDC","72CDD","72CE5","72CE6","72CE7","72CE8","72CE9","72CEA","72CEB","72CEC","72CED","72CEE","72CEF","72CF0","72CF1","72CF2","72CF3","72CF4","72CF5","72CF6","72CF7","72CF8","72CF9","72CFA","72CFB","72CFC","72CFD","72CFE","72CFF","72D00","72D01","72D02","72D03","72D04","72D05","72D06","72D07","72D08","72D0A","72D0B","72D0C","72D0D","72D0E","72D0F","72D10","72D11","72D13","72D14","72D15","72D16","72D17","72D18","72D19","72D1A","72D1B","72D1C","72D1D","72D1E","72D1F","72D20","72D21","72D22","72D23","72D24","72D26","72D27","72D28","72D29","72D2A","72D2B","72D2C","72D2D","72D2E","72D31","72D33","72D51","72D52","72D65","72D66","72D67","72D68","72D69","72D6A","72D6B","72D6C","72D6D","72D6E","72D6F","72D70","72D71","72D72","72D73","72D74","72D75","72D76","72D77","72D78","72D79","72D7A","72D7B","72D7C","72D7D","72D7E","72D7F","72D80","72D81","72D82","72D83","72D84","72D85","72D86","72D87","72D88","72D89","72D8A","72D8B","72D8C","72D8D","72D8E","72D8F","72D90","72D91","72D92","72D93","72D94","72D95","72D96","72D97","72D98","72D99","72D9A","72D9B","72D9C","72D9D","72D9E","72D9F","72DA0","72DA1","72DA2","72DA3","72DA4","72DA5","72DA6","72DA7","72DA8","72DA9","72DAA","72DAB","72DAC","72DAD","72DAE","72DAF","72DB0","72DB1","72DB2","72DB3","72DB4","72DB5","72DB6","72DB7","72DB8","72DB9","72DBA","72DBB","72DBC","72DBD","72DBE","72DBF","72DC0","72DC1","72DC2","72DC3","72DC4","72DC5","72DC6","72DC7","72DC8","72DC9","72DCA","72DCB","72DCC","72DCD","72DCE","72DCF","72DD0","72DD1","72DD2","72DD3","72DD4","72DD5","72DD6","72DD7","72DD8","72DD9","72DDA","72DDB","72DDC","72DDD","72DDE","72DDF","72DE0","72DE1","72DE2","72DE3","72DE4","72DE5","72DE6","72DE7","72DE8","72DE9","72DEA","72DEB","72DEC","72DED","72DEE","72DEF","72DF0","72DF1","72DF2","72DF3","72DF4","72DF5","72DF6","72DF7","72DF8","72DF9","72DFA","72DFB","72DFC","72DFD","72DFE","72DFF","72E00","72E01","72E02","72E03","72E04","72E05","72E06","72E07","72E08","72E09","72E0A","72E0B","72E0C","72E0D","72E0E","72E0F","72E10","72E11","72E12","72E13","72E14","72E15","72E16","72E17","72E18","72E19","72E1A","72E1B","72E1C","72E1D","72E1E","72E1F","72E20","72E21","72E22","72E23","72E24","72E25","72E26","72E27","72E28","72E29","72E2A","72E2B","72E2C","72E2D","72E2E","72E2F","72E30","72E31","72E32","72E33","72E34","72E35","72E36","72E37","72E38","72E39","72E3A","72E3B","72E3C","72E3D","72E3E","72E3F","72E40","72E41","72E42","72E43","72E44","72E45","72E46","72E47","72E48","72E49","72E4A","72E4B","72E4C","72E4D","72E4E","72E4F","72E50","72E51","72E52","72E53","72E54","72E55","72E56","72E57","72E58","72E59","72E5A","72E5B","72E5C","72E5D","72E5E","72E5F","72E60","72E61","72E62","72E63","72E64","72E65","72E66","72E67","72E68","72E69","72E6A","72E6B","72E6C","72E6D","72E6E","72E6F","72E70","72E71","72E72","72E73","72E74","72E75","72E76","72E77","72E78","72E79","72E7A","72E7B","72E7E","72E7F","72E85","72E86","72E87","72E88","72E8D","72E8E","72E8F","72E90","72E92","72E93","72E99","72EBB","72EBC","72EBD","72EBE","72EBF","72EC0","72EC1","72EC2","72EC4","72EC5","72EC6","72EC7","72EC8","72EC9","72ECA","72ECB","72ECC","72ECD","72ECE","72ED0","72ED1","72ED2","72ED3","72ED4","72ED5","72ED6","72ED7","72ED8","72ED9","72EDA","72F07","72F08","72F09","72F0A","72F0C"]} | yes | equipment_light_gray | [0.88,0.89,0.88] | 0.45 | 0.28 | Referencia visual de fotografías públicas de Jinhong Gas / fabricante. Apariencia provisional para coordinación; fotografías oficiales pueden orientar el color, pero no acreditan el material, el acabado ni el equipo concreto. | La apariencia no certifica el material físico ni el acabado de fabricación. | BIM · Equipos | AC1001A | Compresor de aire AC1001A | IfcCompressor | {"documented":[{"label":"Dimensión X local del bastidor de referencia CAD","value":2.35,"unit":"m","source":"EQ-CARGAS-20260825 · contorno CAD · handles 3F3","status":"derivado"},{"label":"Dimensión Y local del bastidor de referencia CAD","value":5.22,"unit":"m","source":"EQ-CARGAS-20260825 · contorno CAD · handles 3F3","status":"derivado"},{"label":"Altura acotada","value":3.38,"unit":"m","source":"EQ-CARGAS-20260825 · handle 52E","status":"documentado"},{"label":"Cota relativa de la superficie de apoyo","value":0.4,"unit":"m","source":"LHD2609-JG00100-20260904 · sección 1 / 1-1 · 28C35, 28C38, 28C3B, 28C89","status":"documentado"}],"geometry":[{"label":"Extensión de la malla en X","value":3.1775829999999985,"unit":"m","source":"Geometría releída del IFC; datum absoluto de proceso provisional","status":"derivado"},{"label":"Extensión de la malla en Y","value":6.404527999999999,"unit":"m","source":"Geometría releída del IFC; datum absoluto de proceso provisional","status":"derivado"},{"label":"Extensión de la malla en Z","value":3.3800000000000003,"unit":"m","source":"Geometría releída del IFC; datum absoluto de proceso provisional","status":"derivado"},{"label":"Cota inferior de visualización","value":286.5,"unit":"m","source":"Geometría releída del IFC; datum absoluto de proceso provisional","status":"derivado"},{"label":"Cota superior de visualización","value":289.88,"unit":"m","source":"Geometría releída del IFC; datum absoluto de proceso provisional","status":"derivado"}],"notes":["Las extensiones de la malla se miden en los ejes del proyecto tras el giro de implantación; no sustituyen las dimensiones locales del fabricante.","La envolvente, su volumen y los espesores de visualización no son volúmenes de material ni cantidades de compra, construcción o fabricación.","Las dimensiones documentadas distinguen cotas explícitas y medidas extraídas de contornos CAD; las dimensiones geométricas describen únicamente la malla publicada.","Las extensiones de la malla refinada y las dimensiones documentadas del contorno o bastidor tienen distinto alcance; las cotas parciales del detalle son provisionales."]} | {"Estado de la planta":"Derivado del CAD y del giro de implantación","Nivel relativo del apoyo (m)":0.4,"Estado del nivel relativo":"Documentado en el plano de cimentaciones","Cero absoluto de visualización (m)":286.1,"Estado del cero absoluto":"Provisional","Cota del apoyo de visualización (m)":286.5,"Desplazamiento aplicado a la malla (m)":0.40000000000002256,"Criterio":"Nivel de apoyo relativo documentado. Se adopta el cero de proceso a 286,10 m solo para visualización; la equivalencia absoluta no está confirmada. No se añade un espesor de montaje sin cota del fabricante."} | ["La máquina está contenida en la envolvente de la cabina acústica; su superposición no acredita una interferencia física.","El bastidor CAD coincide con la referencia de 2,35 × 5,22 m del plano de cargas, pero cuerpos y auxiliares del detalle de abril sobresalen de esa referencia, hasta aproximadamente 1,048 m por el extremo sur y 0,246 m por el lado oeste. Extensión geométrica resultante: 2,595899 × 6,268101 × 3,38 m, derivada y pendiente de coordinación entre revisiones. Permanecen dentro de la cabina acústica. Compatibilidad de revisión pendiente de fabricante.","Todas las alturas parciales son hipótesis de visualización; solo la altura total de 3,38 m está acotada.","Las regiones del dibujo se usan como envolventes de cuerpos; la identificación funcional y la cota Z de cada pieza requieren verificación.","Pequeños taladros, tornillería y detalles interiores de las regiones no se extruyen como vacíos de fabricación.","El bastidor documentado mide 2,35 × 5,22 m. Los accesorios del detalle de abril sobresalen; el conjunto refinado ocupa aproximadamente 2,596 × 6,268 m en ejes del fabricante, pendiente de coordinación entre revisiones.","El acabado de grout HA-35 de 50 mm termina en +0,400; el hormigón termina en +0,350. La losa MAC contigua termina en +0,200.","El cero absoluto de la revisión no está definido; 286,10 m sigue siendo una hipótesis de coordinación.","Se alinea el punto inferior del conjunto del equipo, incluidos los pies ya representados, con la superficie de apoyo terminada; no se añade un espesor de calzos, placa o grout del fabricante no documentado."] | {"revision":"Detalle en planta de 2026-04-30 coordinado de forma preliminar con envolventes y alturas de 2026-08-25","status":"provisional","verticalRule":"Altura total documentada: 3,38 m. Plataforma gráfica de 0,15 m; los cuerpos extraídos de la planta reciben alturas provisionales entre 1,00 y 3,38 m, detalladas por subvolumen. No se dispone de alzado acotado de cada componente.","partCount":26,"source":{"documentId":"EQ-IMPLANTACION-20260430","title":"Plano del fabricante: implantación de equipos","sheet":"LHD2609-GD01000 · espacio modelo","date":"2026-04-30"},"heightSource":{"documentId":"EQ-CARGAS-20260825","title":"Plano del fabricante: cargas de equipos","sheet":"Espacio modelo","date":"2026-08-25"},"unconfirmedDimensions":["Todas las alturas parciales son hipótesis de visualización; solo la altura total de 3,38 m está acotada.","Las regiones del dibujo se usan como envolventes de cuerpos; la identificación funcional y la cota Z de cada pieza requieren verificación.","Pequeños taladros, tornillería y detalles interiores de las regiones no se extruyen como vacíos de fabricación."],"quantityUse":"Magnitudes de la geometría representada; no son cantidades de material, obra, compra, capacidad útil ni fabricación. En geometrías compuestas se suman superficies y volúmenes de partes y pueden existir solapes no depurados.","partsAreBOM":false} | equipment_component | {"min":[48.139687,70.121823,1.5],"max":[51.31727,76.526351,4.88]} | {"boundingBoxM":{"min":[48.139687,70.121823,1.5],"max":[51.31727,76.526351,4.88]},"extentsM":[3.1775829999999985,6.404527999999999,3.38],"meshSurfaceM2":165.1982435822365,"meshVolumeM3":20.17009895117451,"closedSolid":true,"windingConsistent":true,"basis":"Submalla exacta de los triángulos del modelo IFC coordinado; separación de componentes sin transformación ni retesselación."} | ["Todas las alturas parciales son hipótesis de visualización; solo la altura total de 3,38 m está acotada.","Las regiones del dibujo se usan como envolventes de cuerpos; la identificación funcional y la cota Z de cada pieza requieren verificación.","Pequeños taladros, tornillería y detalles interiores de las regiones no se extruyen como vacíos de fabricación.","La separación gráfica no aporta cotas de fabricación ni identifica piezas internas no documentadas.","Los materiales y acabados permanecen provisionales; las fotografías públicas solo orientan la apariencia."] | {"id":"AC1001A--cad-region-003","sourcePartId":"AC1001A--cad-region-003","name":"Cuerpo de equipo · región CAD 3","role":"equipment_component","classificationStatus":"provisional","classificationBasis":"Rol del subvolumen gráfico según el activo de detalle; identidad de fabricación no confirmada.","parentEquipmentId":"AC1001A","parentEquipmentGuid":"1ZhOcwnsbMzxhqtlvKa3pG","isAssemblyIdentityCarrier":false,"sourceFaceRange":[68,124],"sourceCurrentFaceIndices":[68,69,70,71,72,73,74,75,76,77,78,79,80,81,82,83,84,85,86,87,88,89,90,91,92,93,94,95,96,97,98,99,100,101,102,103,104,105,106,107,108,109,110,111,112,113,114,115,116,117,118,119,120,121,122,123],"sourceMeshSha256":"7b60c904c9d84d22fded9be34af09a09a9c198ec8e75e61902634d5e4064c761","sourceVertexIndices":[40,41,42,43,44,45,46,47,48,49,50,51,52,53,54,55,56,57,58,59,60,61,62,63,64,65,66,67,68,69],"separationMethod":"Partición exacta de triángulos existentes; coordenadas y orientación de caras conservadas.","quantityUse":"Magnitudes geométricas del subvolumen; no son cantidades netas de material, fabricación, suministro o capacidad."} | {"id":"AC1001A","name":"Compresor de aire AC1001A","relationship":"decomposed_component","parentShapeMeaning":"La forma del objeto que conserva el ID del equipo es únicamente su componente principal; el conjunto completo requiere sus hijos."} | {"kind":"through_parent","parentEquipmentId":"AC1001A","directAnchorageVerified":false,"note":"La relación del conjunto con cimentaciones se conserva en el objeto que mantiene el ID del equipo; no se atribuye fijación directa a cada subcomponente."} | Documento de implantación y apoyo del conjunto padre; no acredita fijación individual de este componente. | AC1001A--cad-region-003 | Cuerpo de equipo · región CAD 3 | Equipos | unknown | equipment_light_gray | {"documentId":"EQ-IMPLANTACION-20260430","title":"Plano del fabricante: implantación de equipos","sheet":"LHD2609-GD01000 · espacio modelo","date":"2026-04-30","componentSourceHandles":["71316","71317","72C0A","72C15","72C2A","72C3B","72C3F","72C41","72C42","72C44","72C45","72C46","72C47","72C48","72C49","72C4A","72C4B","72C4C","72C4D","72C4E","72C4F","72C50","72C51","72C52","72C53","72C54","72C55","72C56","72C57","72C58","72C59","72C5A","72C5B","72C5C","72C5D","72C5E","72C5F","72C60","72C61","72C62","72C63","72C64","72C65","72C66","72C67","72C68","72C69","72C6A","72C6B","72C6C","72C6D","72C6E","72C6F","72C70","72C71","72C72","72C73","72C74","72C75","72C76","72C77","72C78","72C79","72C7A","72C7B","72C7C","72C7D","72C7E","72C7F","72C80","72C84","72C88","72C89","72C9E","72CA1","72CA4","72CA7","72CAA","72CAD","72CB0","72CB3","72CB6","72CB9","72CBC","72CBF","72CC2","72CC5","72CC8","72CCB","72CCE","72CD1","72CD4","72CD7","72CDA","72CDC","72CDD","72CE5","72CE6","72CE7","72CE8","72CE9","72CEA","72CEB","72CEC","72CED","72CEE","72CEF","72CF0","72CF1","72CF2","72CF3","72CF4","72CF5","72CF6","72CF7","72CF8","72CF9","72CFA","72CFB","72CFC","72CFD","72CFE","72CFF","72D00","72D01","72D02","72D03","72D04","72D05","72D06","72D07","72D08","72D0A","72D0B","72D0C","72D0D","72D0E","72D0F","72D10","72D11","72D13","72D14","72D15","72D16","72D17","72D18","72D19","72D1A","72D1B","72D1C","72D1D","72D1E","72D1F","72D20","72D21","72D22","72D23","72D24","72D26","72D27","72D28","72D29","72D2A","72D2B","72D2C","72D2D","72D2E","72D31","72D33","72D51","72D52","72D65","72D66","72D67","72D68","72D69","72D6A","72D6B","72D6C","72D6D","72D6E","72D6F","72D70","72D71","72D72","72D73","72D74","72D75","72D76","72D77","72D78","72D79","72D7A","72D7B","72D7C","72D7D","72D7E","72D7F","72D80","72D81","72D82","72D83","72D84","72D85","72D86","72D87","72D88","72D89","72D8A","72D8B","72D8C","72D8D","72D8E","72D8F","72D90","72D91","72D92","72D93","72D94","72D95","72D96","72D97","72D98","72D99","72D9A","72D9B","72D9C","72D9D","72D9E","72D9F","72DA0","72DA1","72DA2","72DA3","72DA4","72DA5","72DA6","72DA7","72DA8","72DA9","72DAA","72DAB","72DAC","72DAD","72DAE","72DAF","72DB0","72DB1","72DB2","72DB3","72DB4","72DB5","72DB6","72DB7","72DB8","72DB9","72DBA","72DBB","72DBC","72DBD","72DBE","72DBF","72DC0","72DC1","72DC2","72DC3","72DC4","72DC5","72DC6","72DC7","72DC8","72DC9","72DCA","72DCB","72DCC","72DCD","72DCE","72DCF","72DD0","72DD1","72DD2","72DD3","72DD4","72DD5","72DD6","72DD7","72DD8","72DD9","72DDA","72DDB","72DDC","72DDD","72DDE","72DDF","72DE0","72DE1","72DE2","72DE3","72DE4","72DE5","72DE6","72DE7","72DE8","72DE9","72DEA","72DEB","72DEC","72DED","72DEE","72DEF","72DF0","72DF1","72DF2","72DF3","72DF4","72DF5","72DF6","72DF7","72DF8","72DF9","72DFA","72DFB","72DFC","72DFD","72DFE","72DFF","72E00","72E01","72E02","72E03","72E04","72E05","72E06","72E07","72E08","72E09","72E0A","72E0B","72E0C","72E0D","72E0E","72E0F","72E10","72E11","72E12","72E13","72E14","72E15","72E16","72E17","72E18","72E19","72E1A","72E1B","72E1C","72E1D","72E1E","72E1F","72E20","72E21","72E22","72E23","72E24","72E25","72E26","72E27","72E28","72E29","72E2A","72E2B","72E2C","72E2D","72E2E","72E2F","72E30","72E31","72E32","72E33","72E34","72E35","72E36","72E37","72E38","72E39","72E3A","72E3B","72E3C","72E3D","72E3E","72E3F","72E40","72E41","72E42","72E43","72E44","72E45","72E46","72E47","72E48","72E49","72E4A","72E4B","72E4C","72E4D","72E4E","72E4F","72E50","72E51","72E52","72E53","72E54","72E55","72E56","72E57","72E58","72E59","72E5A","72E5B","72E5C","72E5D","72E5E","72E5F","72E60","72E61","72E62","72E63","72E64","72E65","72E66","72E67","72E68","72E69","72E6A","72E6B","72E6C","72E6D","72E6E","72E6F","72E70","72E71","72E72","72E73","72E74","72E75","72E76","72E77","72E78","72E79","72E7A","72E7B","72E7E","72E7F","72E85","72E86","72E87","72E88","72E8D","72E8E","72E8F","72E90","72E92","72E93","72E99","72EBB","72EBC","72EBD","72EBE","72EBF","72EC0","72EC1","72EC2","72EC4","72EC5","72EC6","72EC7","72EC8","72EC9","72ECA","72ECB","72ECC","72ECD","72ECE","72ED0","72ED1","72ED2","72ED3","72ED4","72ED5","72ED6","72ED7","72ED8","72ED9","72EDA","72F07","72F08","72F09","72F0A","72F0C"]} | Submalla de triángulos existentes; no hay nueva posición ni nuevas caras. | Cotas globales del conjunto conservadas aparte; las dimensiones de esta ficha son de la submalla. | Coordinación del conjunto padre; anclaje directo individual no acreditado. | Superficie y volumen geométricos brutos; no constituyen cantidades netas de obra, material o fabricación. | Plano general y dimensiones globales de AC1001A; no se asignan esas dimensiones globales a este componente. | ["71316","71317","72C0A","72C15","72C2A","72C3B","72C3F","72C41","72C42","72C44","72C45","72C46","72C47","72C48","72C49","72C4A","72C4B","72C4C","72C4D","72C4E","72C4F","72C50","72C51","72C52","72C53","72C54","72C55","72C56","72C57","72C58","72C59","72C5A","72C5B","72C5C","72C5D","72C5E","72C5F","72C60","72C61","72C62","72C63","72C64","72C65","72C66","72C67","72C68","72C69","72C6A","72C6B","72C6C","72C6D","72C6E","72C6F","72C70","72C71","72C72","72C73","72C74","72C75","72C76","72C77","72C78","72C79","72C7A","72C7B","72C7C","72C7D","72C7E","72C7F","72C80","72C84","72C88","72C89","72C9E","72CA1","72CA4","72CA7","72CAA","72CAD","72CB0","72CB3","72CB6","72CB9","72CBC","72CBF","72CC2","72CC5","72CC8","72CCB","72CCE","72CD1","72CD4","72CD7","72CDA","72CDC","72CDD","72CE5","72CE6","72CE7","72CE8","72CE9","72CEA","72CEB","72CEC","72CED","72CEE","72CEF","72CF0","72CF1","72CF2","72CF3","72CF4","72CF5","72CF6","72CF7","72CF8","72CF9","72CFA","72CFB","72CFC","72CFD","72CFE","72CFF","72D00","72D01","72D02","72D03","72D04","72D05","72D06","72D07","72D08","72D0A","72D0B","72D0C","72D0D","72D0E","72D0F","72D10","72D11","72D13","72D14","72D15","72D16","72D17","72D18","72D19","72D1A","72D1B","72D1C","72D1D","72D1E","72D1F","72D20","72D21","72D22","72D23","72D24","72D26","72D27","72D28","72D29","72D2A","72D2B","72D2C","72D2D","72D2E","72D31","72D33","72D51","72D52","72D65","72D66","72D67","72D68","72D69","72D6A","72D6B","72D6C","72D6D","72D6E","72D6F","72D70","72D71","72D72","72D73","72D74","72D75","72D76","72D77","72D78","72D79","72D7A","72D7B","72D7C","72D7D","72D7E","72D7F","72D80","72D81","72D82","72D83","72D84","72D85","72D86","72D87","72D88","72D89","72D8A","72D8B","72D8C","72D8D","72D8E","72D8F","72D90","72D91","72D92","72D93","72D94","72D95","72D96","72D97","72D98","72D99","72D9A","72D9B","72D9C","72D9D","72D9E","72D9F","72DA0","72DA1","72DA2","72DA3","72DA4","72DA5","72DA6","72DA7","72DA8","72DA9","72DAA","72DAB","72DAC","72DAD","72DAE","72DAF","72DB0","72DB1","72DB2","72DB3","72DB4","72DB5","72DB6","72DB7","72DB8","72DB9","72DBA","72DBB","72DBC","72DBD","72DBE","72DBF","72DC0","72DC1","72DC2","72DC3","72DC4","72DC5","72DC6","72DC7","72DC8","72DC9","72DCA","72DCB","72DCC","72DCD","72DCE","72DCF","72DD0","72DD1","72DD2","72DD3","72DD4","72DD5","72DD6","72DD7","72DD8","72DD9","72DDA","72DDB","72DDC","72DDD","72DDE","72DDF","72DE0","72DE1","72DE2","72DE3","72DE4","72DE5","72DE6","72DE7","72DE8","72DE9","72DEA","72DEB","72DEC","72DED","72DEE","72DEF","72DF0","72DF1","72DF2","72DF3","72DF4","72DF5","72DF6","72DF7","72DF8","72DF9","72DFA","72DFB","72DFC","72DFD","72DFE","72DFF","72E00","72E01","72E02","72E03","72E04","72E05","72E06","72E07","72E08","72E09","72E0A","72E0B","72E0C","72E0D","72E0E","72E0F","72E10","72E11","72E12","72E13","72E14","72E15","72E16","72E17","72E18","72E19","72E1A","72E1B","72E1C","72E1D","72E1E","72E1F","72E20","72E21","72E22","72E23","72E24","72E25","72E26","72E27","72E28","72E29","72E2A","72E2B","72E2C","72E2D","72E2E","72E2F","72E30","72E31","72E32","72E33","72E34","72E35","72E36","72E37","72E38","72E39","72E3A","72E3B","72E3C","72E3D","72E3E","72E3F","72E40","72E41","72E42","72E43","72E44","72E45","72E46","72E47","72E48","72E49","72E4A","72E4B","72E4C","72E4D","72E4E","72E4F","72E50","72E51","72E52","72E53","72E54","72E55","72E56","72E57","72E58","72E59","72E5A","72E5B","72E5C","72E5D","72E5E","72E5F","72E60","72E61","72E62","72E63","72E64","72E65","72E66","72E67","72E68","72E69","72E6A","72E6B","72E6C","72E6D","72E6E","72E6F","72E70","72E71","72E72","72E73","72E74","72E75","72E76","72E77","72E78","72E79","72E7A","72E7B","72E7E","72E7F","72E85","72E86","72E87","72E88","72E8D","72E8E","72E8F","72E90","72E92","72E93","72E99","72EBB","72EBC","72EBD","72EBE","72EBF","72EC0","72EC1","72EC2","72EC4","72EC5","72EC6","72EC7","72EC8","72EC9","72ECA","72ECB","72ECC","72ECD","72ECE","72ED0","72ED1","72ED2","72ED3","72ED4","72ED5","72ED6","72ED7","72ED8","72ED9","72EDA","72F07","72F08","72F09","72F0A","72F0C"] | 1 | no | Submalla exacta; interpretación funcional y cotas parciales provisionales.
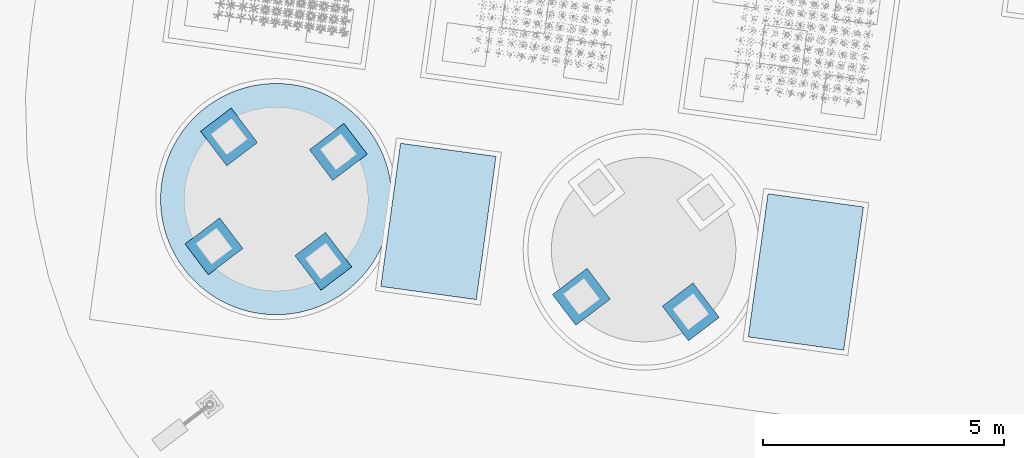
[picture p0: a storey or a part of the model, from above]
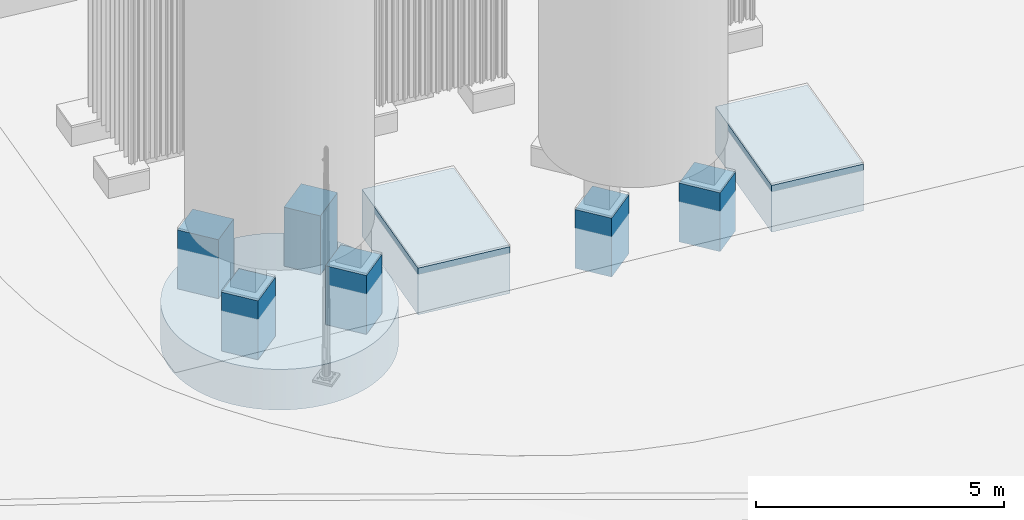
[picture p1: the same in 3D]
Properties of the parts of a building model (IFC4), part 27 of 134

# IfcBuildingElementProxy (140)
Name | Description | Document | Extensión de la malla en X (m) = ExtensionX (m) | Extensión de la malla en Y (m) = ExtensionY (m) | Extensión de la malla en Z (m) = ExtensionZ (m) | Cota inferior de visualización (m) | Cota superior de visualización (m) | SuperficieDeLaMalla (m2) | VolumenGeometrico (m3) | level | category = Categoria = Funcion | representationKind | material | dimensions | JH_InformacionBIM, source = DocumentoFuente | positioning = PosicionYEstado | issues | detailGeometry | geometryMetrics | installationSource | layerId = IdentificadorCapa | visualLayer | materialAppearance | componentSeparation | visualizationIdentity | classification | appearance | Disciplina | Material | Capa BIM = NombreCapa | Acabado de visualización = Acabado | Estado del acabado = Estado | Identificador | JH_Trazabilidad, IncidenciasPendientes | UsoDeLasMagnitudes | JH_EvidenciaDeMaterial, source | JH_DetalleGeometrico, source | VisibilidadInicial | Perfil | ColorRGB | Rugosidad | Metallicidad | Referencia | Nota | Group | parentEquipmentId = Identificador del equipo padre | parentEquipmentName = Equipo padre | parentEquipmentIfcClass | parentEquipmentDimensions | parentEquipmentPositioning | parentEquipmentIssues | parentEquipmentDetail | componentRole = Rol del componente | assemblyBBox | assemblyGeometryMetrics | manufacturerDetailsPending | component | assembly | foundationRelationship | installationSourceScope | Identificador del elemento = sourcePartId | Componente | Capa de visualización | Estado del material | Perfil visual del material | Fuente del componente | Criterio de partición | Criterio de las dimensiones | Relación con cimentaciones | Aplicabilidad de las mediciones | Referencia dimensional del conjunto | sourceHandles | partCount | partsAreBOM | status
Compresor de aire AC1001A · Cuerpo de equipo · región CAD 11 | Componente de equipo · cuerpo o accesorio | Plano del fabricante: implantación de equipos · referencia E7 | 0.257596 | 0.733161 | 2.15 | 286.65 | 288.8 | 4.46214 | 0.226302 | Apoyo relativo +0.400 m; cero absoluto provisional | Componente de equipo · cuerpo o accesorio | equipmentComponent | {"name":"No especificado","source":"Sin especificación de material en la documentación revisada","status":"unknown"} | {"documented":[{"label":"Referencia dimensional del conjunto","value":"Plano general y dimensiones globales de AC1001A; no se asignan esas dimensiones globales a este componente.","unit":"","source":"EQ-IMPLANTACION-20260430 · LHD2609-GD01000 · espacio modelo","status":"referencia_del_conjunto"}],"geometry":[{"label":"Extensión de la malla en X","value":0.2575959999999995,"unit":"m","source":"Geometría releída del IFC; datum absoluto de proceso provisional","status":"derivado"},{"label":"Extensión de la malla en Y","value":0.7331610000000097,"unit":"m","source":"Geometría releída del IFC; datum absoluto de proceso provisional","status":"derivado"},{"label":"Extensión de la malla en Z","value":2.15,"unit":"m","source":"Geometría releída del IFC; datum absoluto de proceso provisional","status":"derivado"},{"label":"Cota inferior de visualización","value":286.65,"unit":"m","source":"Geometría releída del IFC; datum absoluto de proceso provisional","status":"derivado"},{"label":"Cota superior de visualización","value":288.8,"unit":"m","source":"Geometría releída del IFC; datum absoluto de proceso provisional","status":"derivado"}],"notes":["Las dimensiones del equipo completo se conservan en parentEquipmentDimensions.","Las extensiones en X/Y son de los ejes del modelo y no sustituyen cotas locales de fabricación.","No se infieren espesores de chapa, tolerancias ni dimensiones de piezas a partir de la partición."]} | {"documentId":"EQ-IMPLANTACION-20260430","title":"Plano del fabricante: implantación de equipos","sheet":"LHD2609-GD01000 · espacio modelo","date":"2026-04-30","componentSourceHandles":["713B1","713E3","713E4","713F7","71621","71623","71670","71671","71676","7167C","7167D","7177D","7177E","71784","71785","72989","72994","72995","72998","7299A","7299E","729A0","729BE","729BF","729C1","729C3","72F34","72F35","72F38","73103","73104","73105","73108","7310A","732E7","73430"]} | {"horizontalStatus":"derivado_del_conjunto","verticalStatus":"derivado_del_conjunto","coordinateSystem":"model_local_m","parentEquipmentId":"AC1001A","transformApplied":false,"note":"Coordenadas copiadas exactamente del equipo coordinado; no se ha movido, girado, elevado ni reescalado este componente.","foundationRelationship":"El apoyo y las cotas de instalación se documentan para el conjunto padre. Esta submalla no acredita un anclaje directo.","meshMinimumAbsoluteElevationM":286.65,"assemblyPlacementField":"parentEquipmentPositioning"} | ["Componente separado de una reconstrucción documental del conjunto. Las alturas y detalles parciales conservan las limitaciones del fabricante registradas en parentEquipmentIssues.","Esta representación exterior no crea una chapa hueca ni añade componentes internos no documentados.","La pertenencia al conjunto no demuestra apoyo o anclaje directo a la cimentación."] | {"source":{"documentId":"EQ-IMPLANTACION-20260430","title":"Plano del fabricante: implantación de equipos","sheet":"LHD2609-GD01000 · espacio modelo","date":"2026-04-30","componentSourceHandles":["713B1","713E3","713E4","713F7","71621","71623","71670","71671","71676","7167C","7167D","7177D","7177E","71784","71785","72989","72994","72995","72998","7299A","7299E","729A0","729BE","729BF","729C1","729C3","72F34","72F35","72F38","73103","73104","73105","73108","7310A","732E7","73430"]},"sourcePartId":"AC1001A--cad-region-011","sourceHandles":["713B1","713E3","713E4","713F7","71621","71623","71670","71671","71676","7167C","7167D","7177D","7177E","71784","71785","72989","72994","72995","72998","7299A","7299E","729A0","729BE","729BF","729C1","729C3","72F34","72F35","72F38","73103","73104","73105","73108","7310A","732E7","73430"],"partCount":1,"partsAreBOM":false,"status":"Submalla exacta; interpretación funcional y cotas parciales provisionales."} | {"boundingBoxM":{"min":[49.86522,73.410282,1.65],"max":[50.122816,74.143443,3.8]},"extentsM":[0.257596,0.733161,2.15],"meshSurfaceM2":4.462144,"meshVolumeM3":0.226302,"closedSolid":true,"basis":"Geometría de coordinación. Los volúmenes de referencia y subcomponentes no son cantidades de material ni componentes de fabricación certificados."} | {"documentId":"LHD2609-JG00100-20260904","title":"Cimentaciones y pedestales de equipos · revisión recibida 04/09/2026","date":"2026-09-04","sheet":"1 / 1-1","sourceHandles":["28C35","28C38","28C3B","28C89"]} | equipment | {"id":"equipment","name":"Equipos"} | {"profileId":"equipment_light_gray","name":"Equipo · gris claro provisional","materialName":"No especificado","physicalMaterialStatus":"unknown","physicalMaterialSource":"Sin especificación de material en la documentación revisada","appearanceStatus":"provisional","appearanceBasis":"Referencia visual de fotografías públicas de Jinhong Gas / fabricante. Apariencia provisional para coordinación; fotografías oficiales pueden orientar el color, pero no acreditan el material, el acabado ni el equipo concreto.","appearanceReferences":["jinhong-official-asu"],"note":"El perfil visual no confirma material, grado ni acabado del componente."} | {"status":"componente_independiente","note":"Objeto independiente seleccionable. Las caras se asignan una sola vez entre todos los componentes del conjunto.","parentEquipmentId":"AC1001A","isAssemblyIdentityCarrier":false} | {"elementId":"AC1001A--cad-region-011","ifcGuid":"38TWLxLYPVt9mFKbyeRZ58","ifcClass":"IfcBuildingElementProxy","buildingId":"process_plant","buildingName":"Planta de proceso","sourceDocumentId":"EQ-IMPLANTACION-20260430","sourceRepresentationKind":"equipmentComponent"} | {"layerId":"equipment","layerName":"Equipos","role":"Componente de equipo · cuerpo o accesorio","basis":"Clasificación por función del elemento; no modifica las especificaciones documentales."} | {"profileId":"equipment_light_gray","name":"Equipo · gris claro provisional","status":"provisional","basis":"Referencia visual de fotografías públicas de Jinhong Gas / fabricante. Apariencia provisional para coordinación; fotografías oficiales pueden orientar el color, pero no acreditan el material, el acabado ni el equipo concreto.","physicalMaterialUnchanged":true} | Equipos | No especificado | Equipos | Equipo · gris claro provisional | provisional | AC1001A--cad-region-011 | ["Componente separado de una reconstrucción documental del conjunto. Las alturas y detalles parciales conservan las limitaciones del fabricante registradas en parentEquipmentIssues.","Esta representación exterior no crea una chapa hueca ni añade componentes internos no documentados.","La pertenencia al conjunto no demuestra apoyo o anclaje directo a la cimentación."] | Geometría de coordinación. Los volúmenes de referencia y subcomponentes no son cantidades de material ni componentes de fabricación certificados. | Sin especificación de material en la documentación revisada | {"documentId":"EQ-IMPLANTACION-20260430","title":"Plano del fabricante: implantación de equipos","sheet":"LHD2609-GD01000 · espacio modelo","date":"2026-04-30","componentSourceHandles":["713B1","713E3","713E4","713F7","71621","71623","71670","71671","71676","7167C","7167D","7177D","7177E","71784","71785","72989","72994","72995","72998","7299A","7299E","729A0","729BE","729BF","729C1","729C3","72F34","72F35","72F38","73103","73104","73105","73108","7310A","732E7","73430"]} | yes | equipment_light_gray | [0.88,0.89,0.88] | 0.45 | 0.28 | Referencia visual de fotografías públicas de Jinhong Gas / fabricante. Apariencia provisional para coordinación; fotografías oficiales pueden orientar el color, pero no acreditan el material, el acabado ni el equipo concreto. | La apariencia no certifica el material físico ni el acabado de fabricación. | BIM · Equipos | AC1001A | Compresor de aire AC1001A | IfcCompressor | {"documented":[{"label":"Dimensión X local del bastidor de referencia CAD","value":2.35,"unit":"m","source":"EQ-CARGAS-20260825 · contorno CAD · handles 3F3","status":"derivado"},{"label":"Dimensión Y local del bastidor de referencia CAD","value":5.22,"unit":"m","source":"EQ-CARGAS-20260825 · contorno CAD · handles 3F3","status":"derivado"},{"label":"Altura acotada","value":3.38,"unit":"m","source":"EQ-CARGAS-20260825 · handle 52E","status":"documentado"},{"label":"Cota relativa de la superficie de apoyo","value":0.4,"unit":"m","source":"LHD2609-JG00100-20260904 · sección 1 / 1-1 · 28C35, 28C38, 28C3B, 28C89","status":"documentado"}],"geometry":[{"label":"Extensión de la malla en X","value":3.1775829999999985,"unit":"m","source":"Geometría releída del IFC; datum absoluto de proceso provisional","status":"derivado"},{"label":"Extensión de la malla en Y","value":6.404527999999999,"unit":"m","source":"Geometría releída del IFC; datum absoluto de proceso provisional","status":"derivado"},{"label":"Extensión de la malla en Z","value":3.3800000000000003,"unit":"m","source":"Geometría releída del IFC; datum absoluto de proceso provisional","status":"derivado"},{"label":"Cota inferior de visualización","value":286.5,"unit":"m","source":"Geometría releída del IFC; datum absoluto de proceso provisional","status":"derivado"},{"label":"Cota superior de visualización","value":289.88,"unit":"m","source":"Geometría releída del IFC; datum absoluto de proceso provisional","status":"derivado"}],"notes":["Las extensiones de la malla se miden en los ejes del proyecto tras el giro de implantación; no sustituyen las dimensiones locales del fabricante.","La envolvente, su volumen y los espesores de visualización no son volúmenes de material ni cantidades de compra, construcción o fabricación.","Las dimensiones documentadas distinguen cotas explícitas y medidas extraídas de contornos CAD; las dimensiones geométricas describen únicamente la malla publicada.","Las extensiones de la malla refinada y las dimensiones documentadas del contorno o bastidor tienen distinto alcance; las cotas parciales del detalle son provisionales."]} | {"Estado de la planta":"Derivado del CAD y del giro de implantación","Nivel relativo del apoyo (m)":0.4,"Estado del nivel relativo":"Documentado en el plano de cimentaciones","Cero absoluto de visualización (m)":286.1,"Estado del cero absoluto":"Provisional","Cota del apoyo de visualización (m)":286.5,"Desplazamiento aplicado a la malla (m)":0.40000000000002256,"Criterio":"Nivel de apoyo relativo documentado. Se adopta el cero de proceso a 286,10 m solo para visualización; la equivalencia absoluta no está confirmada. No se añade un espesor de montaje sin cota del fabricante."} | ["La máquina está contenida en la envolvente de la cabina acústica; su superposición no acredita una interferencia física.","El bastidor CAD coincide con la referencia de 2,35 × 5,22 m del plano de cargas, pero cuerpos y auxiliares del detalle de abril sobresalen de esa referencia, hasta aproximadamente 1,048 m por el extremo sur y 0,246 m por el lado oeste. Extensión geométrica resultante: 2,595899 × 6,268101 × 3,38 m, derivada y pendiente de coordinación entre revisiones. Permanecen dentro de la cabina acústica. Compatibilidad de revisión pendiente de fabricante.","Todas las alturas parciales son hipótesis de visualización; solo la altura total de 3,38 m está acotada.","Las regiones del dibujo se usan como envolventes de cuerpos; la identificación funcional y la cota Z de cada pieza requieren verificación.","Pequeños taladros, tornillería y detalles interiores de las regiones no se extruyen como vacíos de fabricación.","El bastidor documentado mide 2,35 × 5,22 m. Los accesorios del detalle de abril sobresalen; el conjunto refinado ocupa aproximadamente 2,596 × 6,268 m en ejes del fabricante, pendiente de coordinación entre revisiones.","El acabado de grout HA-35 de 50 mm termina en +0,400; el hormigón termina en +0,350. La losa MAC contigua termina en +0,200.","El cero absoluto de la revisión no está definido; 286,10 m sigue siendo una hipótesis de coordinación.","Se alinea el punto inferior del conjunto del equipo, incluidos los pies ya representados, con la superficie de apoyo terminada; no se añade un espesor de calzos, placa o grout del fabricante no documentado."] | {"revision":"Detalle en planta de 2026-04-30 coordinado de forma preliminar con envolventes y alturas de 2026-08-25","status":"provisional","verticalRule":"Altura total documentada: 3,38 m. Plataforma gráfica de 0,15 m; los cuerpos extraídos de la planta reciben alturas provisionales entre 1,00 y 3,38 m, detalladas por subvolumen. No se dispone de alzado acotado de cada componente.","partCount":26,"source":{"documentId":"EQ-IMPLANTACION-20260430","title":"Plano del fabricante: implantación de equipos","sheet":"LHD2609-GD01000 · espacio modelo","date":"2026-04-30"},"heightSource":{"documentId":"EQ-CARGAS-20260825","title":"Plano del fabricante: cargas de equipos","sheet":"Espacio modelo","date":"2026-08-25"},"unconfirmedDimensions":["Todas las alturas parciales son hipótesis de visualización; solo la altura total de 3,38 m está acotada.","Las regiones del dibujo se usan como envolventes de cuerpos; la identificación funcional y la cota Z de cada pieza requieren verificación.","Pequeños taladros, tornillería y detalles interiores de las regiones no se extruyen como vacíos de fabricación."],"quantityUse":"Magnitudes de la geometría representada; no son cantidades de material, obra, compra, capacidad útil ni fabricación. En geometrías compuestas se suman superficies y volúmenes de partes y pueden existir solapes no depurados.","partsAreBOM":false} | equipment_component | {"min":[48.139687,70.121823,1.5],"max":[51.31727,76.526351,4.88]} | {"boundingBoxM":{"min":[48.139687,70.121823,1.5],"max":[51.31727,76.526351,4.88]},"extentsM":[3.1775829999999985,6.404527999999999,3.38],"meshSurfaceM2":165.1982435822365,"meshVolumeM3":20.17009895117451,"closedSolid":true,"windingConsistent":true,"basis":"Submalla exacta de los triángulos del modelo IFC coordinado; separación de componentes sin transformación ni retesselación."} | ["Todas las alturas parciales son hipótesis de visualización; solo la altura total de 3,38 m está acotada.","Las regiones del dibujo se usan como envolventes de cuerpos; la identificación funcional y la cota Z de cada pieza requieren verificación.","Pequeños taladros, tornillería y detalles interiores de las regiones no se extruyen como vacíos de fabricación.","La separación gráfica no aporta cotas de fabricación ni identifica piezas internas no documentadas.","Los materiales y acabados permanecen provisionales; las fotografías públicas solo orientan la apariencia."] | {"id":"AC1001A--cad-region-011","sourcePartId":"AC1001A--cad-region-011","name":"Cuerpo de equipo · región CAD 11","role":"equipment_component","classificationStatus":"provisional","classificationBasis":"Rol del subvolumen gráfico según el activo de detalle; identidad de fabricación no confirmada.","parentEquipmentId":"AC1001A","parentEquipmentGuid":"1ZhOcwnsbMzxhqtlvKa3pG","isAssemblyIdentityCarrier":false,"sourceFaceRange":[268,356],"sourceCurrentFaceIndices":[268,269,270,271,272,273,274,275,276,277,278,279,280,281,282,283,284,285,286,287,288,289,290,291,292,293,294,295,296,297,298,299,300,301,302,303,304,305,306,307,308,309,310,311,312,313,314,315,316,317,318,319,320,321,322,323,324,325,326,327,328,329,330,331,332,333,334,335,336,337,338,339,340,341,342,343,344,345,346,347,348,349,350,351,352,353,354,355],"sourceMeshSha256":"7b60c904c9d84d22fded9be34af09a09a9c198ec8e75e61902634d5e4064c761","sourceVertexIndices":[154,155,156,157,158,159,160,161,162,163,164,165,166,167,168,169,170,171,172,173,174,175,176,177,178,179,180,181,182,183,184,185,186,187,188,189,190,191,192,193,194,195,196,197,198,199],"separationMethod":"Partición exacta de triángulos existentes; coordenadas y orientación de caras conservadas.","quantityUse":"Magnitudes geométricas del subvolumen; no son cantidades netas de material, fabricación, suministro o capacidad."} | {"id":"AC1001A","name":"Compresor de aire AC1001A","relationship":"decomposed_component","parentShapeMeaning":"La forma del objeto que conserva el ID del equipo es únicamente su componente principal; el conjunto completo requiere sus hijos."} | {"kind":"through_parent","parentEquipmentId":"AC1001A","directAnchorageVerified":false,"note":"La relación del conjunto con cimentaciones se conserva en el objeto que mantiene el ID del equipo; no se atribuye fijación directa a cada subcomponente."} | Documento de implantación y apoyo del conjunto padre; no acredita fijación individual de este componente. | AC1001A--cad-region-011 | Cuerpo de equipo · región CAD 11 | Equipos | unknown | equipment_light_gray | {"documentId":"EQ-IMPLANTACION-20260430","title":"Plano del fabricante: implantación de equipos","sheet":"LHD2609-GD01000 · espacio modelo","date":"2026-04-30","componentSourceHandles":["713B1","713E3","713E4","713F7","71621","71623","71670","71671","71676","7167C","7167D","7177D","7177E","71784","71785","72989","72994","72995","72998","7299A","7299E","729A0","729BE","729BF","729C1","729C3","72F34","72F35","72F38","73103","73104","73105","73108","7310A","732E7","73430"]} | Submalla de triángulos existentes; no hay nueva posición ni nuevas caras. | Cotas globales del conjunto conservadas aparte; las dimensiones de esta ficha son de la submalla. | Coordinación del conjunto padre; anclaje directo individual no acreditado. | Superficie y volumen geométricos brutos; no constituyen cantidades netas de obra, material o fabricación. | Plano general y dimensiones globales de AC1001A; no se asignan esas dimensiones globales a este componente. | ["713B1","713E3","713E4","713F7","71621","71623","71670","71671","71676","7167C","7167D","7177D","7177E","71784","71785","72989","72994","72995","72998","7299A","7299E","729A0","729BE","729BF","729C1","729C3","72F34","72F35","72F38","73103","73104","73105","73108","7310A","732E7","73430"] | 1 | no | Submalla exacta; interpretación funcional y cotas parciales provisionales.
Compresor de aire AC1001A · Cuerpo de equipo · región CAD 12 | Componente de equipo · cuerpo o accesorio | Plano del fabricante: implantación de equipos · referencia E7 | 0.211568 | 0.556179 | 1.6 | 286.65 | 288.25 | 2.33092 | 0.120607 | Apoyo relativo +0.400 m; cero absoluto provisional | Componente de equipo · cuerpo o accesorio | equipmentComponent | {"name":"No especificado","source":"Sin especificación de material en la documentación revisada","status":"unknown"} | {"documented":[{"label":"Referencia dimensional del conjunto","value":"Plano general y dimensiones globales de AC1001A; no se asignan esas dimensiones globales a este componente.","unit":"","source":"EQ-IMPLANTACION-20260430 · LHD2609-GD01000 · espacio modelo","status":"referencia_del_conjunto"}],"geometry":[{"label":"Extensión de la malla en X","value":0.21156799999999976,"unit":"m","source":"Geometría releída del IFC; datum absoluto de proceso provisional","status":"derivado"},{"label":"Extensión de la malla en Y","value":0.5561790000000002,"unit":"m","source":"Geometría releída del IFC; datum absoluto de proceso provisional","status":"derivado"},{"label":"Extensión de la malla en Z","value":1.6,"unit":"m","source":"Geometría releída del IFC; datum absoluto de proceso provisional","status":"derivado"},{"label":"Cota inferior de visualización","value":286.65,"unit":"m","source":"Geometría releída del IFC; datum absoluto de proceso provisional","status":"derivado"},{"label":"Cota superior de visualización","value":288.25,"unit":"m","source":"Geometría releída del IFC; datum absoluto de proceso provisional","status":"derivado"}],"notes":["Las dimensiones del equipo completo se conservan en parentEquipmentDimensions.","Las extensiones en X/Y son de los ejes del modelo y no sustituyen cotas locales de fabricación.","No se infieren espesores de chapa, tolerancias ni dimensiones de piezas a partir de la partición."]} | {"documentId":"EQ-IMPLANTACION-20260430","title":"Plano del fabricante: implantación de equipos","sheet":"LHD2609-GD01000 · espacio modelo","date":"2026-04-30","componentSourceHandles":["71A33","73144","73147","73162","73163","73175"]} | {"horizontalStatus":"derivado_del_conjunto","verticalStatus":"derivado_del_conjunto","coordinateSystem":"model_local_m","parentEquipmentId":"AC1001A","transformApplied":false,"note":"Coordenadas copiadas exactamente del equipo coordinado; no se ha movido, girado, elevado ni reescalado este componente.","foundationRelationship":"El apoyo y las cotas de instalación se documentan para el conjunto padre. Esta submalla no acredita un anclaje directo.","meshMinimumAbsoluteElevationM":286.65,"assemblyPlacementField":"parentEquipmentPositioning"} | ["Componente separado de una reconstrucción documental del conjunto. Las alturas y detalles parciales conservan las limitaciones del fabricante registradas en parentEquipmentIssues.","Esta representación exterior no crea una chapa hueca ni añade componentes internos no documentados.","La pertenencia al conjunto no demuestra apoyo o anclaje directo a la cimentación."] | {"source":{"documentId":"EQ-IMPLANTACION-20260430","title":"Plano del fabricante: implantación de equipos","sheet":"LHD2609-GD01000 · espacio modelo","date":"2026-04-30","componentSourceHandles":["71A33","73144","73147","73162","73163","73175"]},"sourcePartId":"AC1001A--cad-region-012","sourceHandles":["71A33","73144","73147","73162","73163","73175"],"partCount":1,"partsAreBOM":false,"status":"Submalla exacta; interpretación funcional y cotas parciales provisionales."} | {"boundingBoxM":{"min":[50.446928,73.767935,1.65],"max":[50.658496,74.324114,3.25]},"extentsM":[0.211568,0.556179,1.6],"meshSurfaceM2":2.33092,"meshVolumeM3":0.120607,"closedSolid":true,"basis":"Geometría de coordinación. Los volúmenes de referencia y subcomponentes no son cantidades de material ni componentes de fabricación certificados."} | {"documentId":"LHD2609-JG00100-20260904","title":"Cimentaciones y pedestales de equipos · revisión recibida 04/09/2026","date":"2026-09-04","sheet":"1 / 1-1","sourceHandles":["28C35","28C38","28C3B","28C89"]} | equipment | {"id":"equipment","name":"Equipos"} | {"profileId":"equipment_light_gray","name":"Equipo · gris claro provisional","materialName":"No especificado","physicalMaterialStatus":"unknown","physicalMaterialSource":"Sin especificación de material en la documentación revisada","appearanceStatus":"provisional","appearanceBasis":"Referencia visual de fotografías públicas de Jinhong Gas / fabricante. Apariencia provisional para coordinación; fotografías oficiales pueden orientar el color, pero no acreditan el material, el acabado ni el equipo concreto.","appearanceReferences":["jinhong-official-asu"],"note":"El perfil visual no confirma material, grado ni acabado del componente."} | {"status":"componente_independiente","note":"Objeto independiente seleccionable. Las caras se asignan una sola vez entre todos los componentes del conjunto.","parentEquipmentId":"AC1001A","isAssemblyIdentityCarrier":false} | {"elementId":"AC1001A--cad-region-012","ifcGuid":"167A4Lr49NkP_gdf6gyXiR","ifcClass":"IfcBuildingElementProxy","buildingId":"process_plant","buildingName":"Planta de proceso","sourceDocumentId":"EQ-IMPLANTACION-20260430","sourceRepresentationKind":"equipmentComponent"} | {"layerId":"equipment","layerName":"Equipos","role":"Componente de equipo · cuerpo o accesorio","basis":"Clasificación por función del elemento; no modifica las especificaciones documentales."} | {"profileId":"equipment_light_gray","name":"Equipo · gris claro provisional","status":"provisional","basis":"Referencia visual de fotografías públicas de Jinhong Gas / fabricante. Apariencia provisional para coordinación; fotografías oficiales pueden orientar el color, pero no acreditan el material, el acabado ni el equipo concreto.","physicalMaterialUnchanged":true} | Equipos | No especificado | Equipos | Equipo · gris claro provisional | provisional | AC1001A--cad-region-012 | ["Componente separado de una reconstrucción documental del conjunto. Las alturas y detalles parciales conservan las limitaciones del fabricante registradas en parentEquipmentIssues.","Esta representación exterior no crea una chapa hueca ni añade componentes internos no documentados.","La pertenencia al conjunto no demuestra apoyo o anclaje directo a la cimentación."] | Geometría de coordinación. Los volúmenes de referencia y subcomponentes no son cantidades de material ni componentes de fabricación certificados. | Sin especificación de material en la documentación revisada | {"documentId":"EQ-IMPLANTACION-20260430","title":"Plano del fabricante: implantación de equipos","sheet":"LHD2609-GD01000 · espacio modelo","date":"2026-04-30","componentSourceHandles":["71A33","73144","73147","73162","73163","73175"]} | yes | equipment_light_gray | [0.88,0.89,0.88] | 0.45 | 0.28 | Referencia visual de fotografías públicas de Jinhong Gas / fabricante. Apariencia provisional para coordinación; fotografías oficiales pueden orientar el color, pero no acreditan el material, el acabado ni el equipo concreto. | La apariencia no certifica el material físico ni el acabado de fabricación. | BIM · Equipos | AC1001A | Compresor de aire AC1001A | IfcCompressor | {"documented":[{"label":"Dimensión X local del bastidor de referencia CAD","value":2.35,"unit":"m","source":"EQ-CARGAS-20260825 · contorno CAD · handles 3F3","status":"derivado"},{"label":"Dimensión Y local del bastidor de referencia CAD","value":5.22,"unit":"m","source":"EQ-CARGAS-20260825 · contorno CAD · handles 3F3","status":"derivado"},{"label":"Altura acotada","value":3.38,"unit":"m","source":"EQ-CARGAS-20260825 · handle 52E","status":"documentado"},{"label":"Cota relativa de la superficie de apoyo","value":0.4,"unit":"m","source":"LHD2609-JG00100-20260904 · sección 1 / 1-1 · 28C35, 28C38, 28C3B, 28C89","status":"documentado"}],"geometry":[{"label":"Extensión de la malla en X","value":3.1775829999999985,"unit":"m","source":"Geometría releída del IFC; datum absoluto de proceso provisional","status":"derivado"},{"label":"Extensión de la malla en Y","value":6.404527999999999,"unit":"m","source":"Geometría releída del IFC; datum absoluto de proceso provisional","status":"derivado"},{"label":"Extensión de la malla en Z","value":3.3800000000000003,"unit":"m","source":"Geometría releída del IFC; datum absoluto de proceso provisional","status":"derivado"},{"label":"Cota inferior de visualización","value":286.5,"unit":"m","source":"Geometría releída del IFC; datum absoluto de proceso provisional","status":"derivado"},{"label":"Cota superior de visualización","value":289.88,"unit":"m","source":"Geometría releída del IFC; datum absoluto de proceso provisional","status":"derivado"}],"notes":["Las extensiones de la malla se miden en los ejes del proyecto tras el giro de implantación; no sustituyen las dimensiones locales del fabricante.","La envolvente, su volumen y los espesores de visualización no son volúmenes de material ni cantidades de compra, construcción o fabricación.","Las dimensiones documentadas distinguen cotas explícitas y medidas extraídas de contornos CAD; las dimensiones geométricas describen únicamente la malla publicada.","Las extensiones de la malla refinada y las dimensiones documentadas del contorno o bastidor tienen distinto alcance; las cotas parciales del detalle son provisionales."]} | {"Estado de la planta":"Derivado del CAD y del giro de implantación","Nivel relativo del apoyo (m)":0.4,"Estado del nivel relativo":"Documentado en el plano de cimentaciones","Cero absoluto de visualización (m)":286.1,"Estado del cero absoluto":"Provisional","Cota del apoyo de visualización (m)":286.5,"Desplazamiento aplicado a la malla (m)":0.40000000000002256,"Criterio":"Nivel de apoyo relativo documentado. Se adopta el cero de proceso a 286,10 m solo para visualización; la equivalencia absoluta no está confirmada. No se añade un espesor de montaje sin cota del fabricante."} | ["La máquina está contenida en la envolvente de la cabina acústica; su superposición no acredita una interferencia física.","El bastidor CAD coincide con la referencia de 2,35 × 5,22 m del plano de cargas, pero cuerpos y auxiliares del detalle de abril sobresalen de esa referencia, hasta aproximadamente 1,048 m por el extremo sur y 0,246 m por el lado oeste. Extensión geométrica resultante: 2,595899 × 6,268101 × 3,38 m, derivada y pendiente de coordinación entre revisiones. Permanecen dentro de la cabina acústica. Compatibilidad de revisión pendiente de fabricante.","Todas las alturas parciales son hipótesis de visualización; solo la altura total de 3,38 m está acotada.","Las regiones del dibujo se usan como envolventes de cuerpos; la identificación funcional y la cota Z de cada pieza requieren verificación.","Pequeños taladros, tornillería y detalles interiores de las regiones no se extruyen como vacíos de fabricación.","El bastidor documentado mide 2,35 × 5,22 m. Los accesorios del detalle de abril sobresalen; el conjunto refinado ocupa aproximadamente 2,596 × 6,268 m en ejes del fabricante, pendiente de coordinación entre revisiones.","El acabado de grout HA-35 de 50 mm termina en +0,400; el hormigón termina en +0,350. La losa MAC contigua termina en +0,200.","El cero absoluto de la revisión no está definido; 286,10 m sigue siendo una hipótesis de coordinación.","Se alinea el punto inferior del conjunto del equipo, incluidos los pies ya representados, con la superficie de apoyo terminada; no se añade un espesor de calzos, placa o grout del fabricante no documentado."] | {"revision":"Detalle en planta de 2026-04-30 coordinado de forma preliminar con envolventes y alturas de 2026-08-25","status":"provisional","verticalRule":"Altura total documentada: 3,38 m. Plataforma gráfica de 0,15 m; los cuerpos extraídos de la planta reciben alturas provisionales entre 1,00 y 3,38 m, detalladas por subvolumen. No se dispone de alzado acotado de cada componente.","partCount":26,"source":{"documentId":"EQ-IMPLANTACION-20260430","title":"Plano del fabricante: implantación de equipos","sheet":"LHD2609-GD01000 · espacio modelo","date":"2026-04-30"},"heightSource":{"documentId":"EQ-CARGAS-20260825","title":"Plano del fabricante: cargas de equipos","sheet":"Espacio modelo","date":"2026-08-25"},"unconfirmedDimensions":["Todas las alturas parciales son hipótesis de visualización; solo la altura total de 3,38 m está acotada.","Las regiones del dibujo se usan como envolventes de cuerpos; la identificación funcional y la cota Z de cada pieza requieren verificación.","Pequeños taladros, tornillería y detalles interiores de las regiones no se extruyen como vacíos de fabricación."],"quantityUse":"Magnitudes de la geometría representada; no son cantidades de material, obra, compra, capacidad útil ni fabricación. En geometrías compuestas se suman superficies y volúmenes de partes y pueden existir solapes no depurados.","partsAreBOM":false} | equipment_component | {"min":[48.139687,70.121823,1.5],"max":[51.31727,76.526351,4.88]} | {"boundingBoxM":{"min":[48.139687,70.121823,1.5],"max":[51.31727,76.526351,4.88]},"extentsM":[3.1775829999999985,6.404527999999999,3.38],"meshSurfaceM2":165.1982435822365,"meshVolumeM3":20.17009895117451,"closedSolid":true,"windingConsistent":true,"basis":"Submalla exacta de los triángulos del modelo IFC coordinado; separación de componentes sin transformación ni retesselación."} | ["Todas las alturas parciales son hipótesis de visualización; solo la altura total de 3,38 m está acotada.","Las regiones del dibujo se usan como envolventes de cuerpos; la identificación funcional y la cota Z de cada pieza requieren verificación.","Pequeños taladros, tornillería y detalles interiores de las regiones no se extruyen como vacíos de fabricación.","La separación gráfica no aporta cotas de fabricación ni identifica piezas internas no documentadas.","Los materiales y acabados permanecen provisionales; las fotografías públicas solo orientan la apariencia."] | {"id":"AC1001A--cad-region-012","sourcePartId":"AC1001A--cad-region-012","name":"Cuerpo de equipo · región CAD 12","role":"equipment_component","classificationStatus":"provisional","classificationBasis":"Rol del subvolumen gráfico según el activo de detalle; identidad de fabricación no confirmada.","parentEquipmentId":"AC1001A","parentEquipmentGuid":"1ZhOcwnsbMzxhqtlvKa3pG","isAssemblyIdentityCarrier":false,"sourceFaceRange":[356,368],"sourceCurrentFaceIndices":[356,357,358,359,360,361,362,363,364,365,366,367],"sourceMeshSha256":"7b60c904c9d84d22fded9be34af09a09a9c198ec8e75e61902634d5e4064c761","sourceVertexIndices":[200,201,202,203,204,205,206,207],"separationMethod":"Partición exacta de triángulos existentes; coordenadas y orientación de caras conservadas.","quantityUse":"Magnitudes geométricas del subvolumen; no son cantidades netas de material, fabricación, suministro o capacidad."} | {"id":"AC1001A","name":"Compresor de aire AC1001A","relationship":"decomposed_component","parentShapeMeaning":"La forma del objeto que conserva el ID del equipo es únicamente su componente principal; el conjunto completo requiere sus hijos."} | {"kind":"through_parent","parentEquipmentId":"AC1001A","directAnchorageVerified":false,"note":"La relación del conjunto con cimentaciones se conserva en el objeto que mantiene el ID del equipo; no se atribuye fijación directa a cada subcomponente."} | Documento de implantación y apoyo del conjunto padre; no acredita fijación individual de este componente. | AC1001A--cad-region-012 | Cuerpo de equipo · región CAD 12 | Equipos | unknown | equipment_light_gray | {"documentId":"EQ-IMPLANTACION-20260430","title":"Plano del fabricante: implantación de equipos","sheet":"LHD2609-GD01000 · espacio modelo","date":"2026-04-30","componentSourceHandles":["71A33","73144","73147","73162","73163","73175"]} | Submalla de triángulos existentes; no hay nueva posición ni nuevas caras. | Cotas globales del conjunto conservadas aparte; las dimensiones de esta ficha son de la submalla. | Coordinación del conjunto padre; anclaje directo individual no acreditado. | Superficie y volumen geométricos brutos; no constituyen cantidades netas de obra, material o fabricación. | Plano general y dimensiones globales de AC1001A; no se asignan esas dimensiones globales a este componente. | ["71A33","73144","73147","73162","73163","73175"] | 1 | no | Submalla exacta; interpretación funcional y cotas parciales provisionales.
Compresor de aire AC1001A · Cuerpo de equipo · región CAD 13 | Componente de equipo · cuerpo o accesorio | Plano del fabricante: implantación de equipos · referencia E7 | 0.328241 | 0.314019 | 0.85 | 286.65 | 287.5 | 1.15032 | 0.069849 | Apoyo relativo +0.400 m; cero absoluto provisional | Componente de equipo · cuerpo o accesorio | equipmentComponent | {"name":"No especificado","source":"Sin especificación de material en la documentación revisada","status":"unknown"} | {"documented":[{"label":"Referencia dimensional del conjunto","value":"Plano general y dimensiones globales de AC1001A; no se asignan esas dimensiones globales a este componente.","unit":"","source":"EQ-IMPLANTACION-20260430 · LHD2609-GD01000 · espacio modelo","status":"referencia_del_conjunto"}],"geometry":[{"label":"Extensión de la malla en X","value":0.32824099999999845,"unit":"m","source":"Geometría releída del IFC; datum absoluto de proceso provisional","status":"derivado"},{"label":"Extensión de la malla en Y","value":0.3140190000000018,"unit":"m","source":"Geometría releída del IFC; datum absoluto de proceso provisional","status":"derivado"},{"label":"Extensión de la malla en Z","value":0.8500000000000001,"unit":"m","source":"Geometría releída del IFC; datum absoluto de proceso provisional","status":"derivado"},{"label":"Cota inferior de visualización","value":286.65,"unit":"m","source":"Geometría releída del IFC; datum absoluto de proceso provisional","status":"derivado"},{"label":"Cota superior de visualización","value":287.5,"unit":"m","source":"Geometría releída del IFC; datum absoluto de proceso provisional","status":"derivado"}],"notes":["Las dimensiones del equipo completo se conservan en parentEquipmentDimensions.","Las extensiones en X/Y son de los ejes del modelo y no sustituyen cotas locales de fabricación.","No se infieren espesores de chapa, tolerancias ni dimensiones de piezas a partir de la partición."]} | {"documentId":"EQ-IMPLANTACION-20260430","title":"Plano del fabricante: implantación de equipos","sheet":"LHD2609-GD01000 · espacio modelo","date":"2026-04-30","componentSourceHandles":["7103B","7103F","71040","71041","71042","71045","71046","71050","71075","71076","7109E","710A0","710A4","710A5","710A6","710A7","710A8","710B1","710B2","710B3","710B4","710B5","710B6","710B7","710B8","710BA","710BB","710BC","710BD","710C1","710C4","710C5","710C6","710CC","710CE","710D3","710D7","710D8","710D9","710DB","710DD","710E4","710E5","710EB","710F0","710F3","710F8","710FC","710FE","7110F","71111","71116","71142","71276","71285","7129B","712A1","712A3","712A9","712AC","71302","71306","7130B","7130F"]} | {"horizontalStatus":"derivado_del_conjunto","verticalStatus":"derivado_del_conjunto","coordinateSystem":"model_local_m","parentEquipmentId":"AC1001A","transformApplied":false,"note":"Coordenadas copiadas exactamente del equipo coordinado; no se ha movido, girado, elevado ni reescalado este componente.","foundationRelationship":"El apoyo y las cotas de instalación se documentan para el conjunto padre. Esta submalla no acredita un anclaje directo.","meshMinimumAbsoluteElevationM":286.65,"assemblyPlacementField":"parentEquipmentPositioning"} | ["Componente separado de una reconstrucción documental del conjunto. Las alturas y detalles parciales conservan las limitaciones del fabricante registradas en parentEquipmentIssues.","Esta representación exterior no crea una chapa hueca ni añade componentes internos no documentados.","La pertenencia al conjunto no demuestra apoyo o anclaje directo a la cimentación."] | {"source":{"documentId":"EQ-IMPLANTACION-20260430","title":"Plano del fabricante: implantación de equipos","sheet":"LHD2609-GD01000 · espacio modelo","date":"2026-04-30","componentSourceHandles":["7103B","7103F","71040","71041","71042","71045","71046","71050","71075","71076","7109E","710A0","710A4","710A5","710A6","710A7","710A8","710B1","710B2","710B3","710B4","710B5","710B6","710B7","710B8","710BA","710BB","710BC","710BD","710C1","710C4","710C5","710C6","710CC","710CE","710D3","710D7","710D8","710D9","710DB","710DD","710E4","710E5","710EB","710F0","710F3","710F8","710FC","710FE","7110F","71111","71116","71142","71276","71285","7129B","712A1","712A3","712A9","712AC","71302","71306","7130B","7130F"]},"sourcePartId":"AC1001A--cad-region-013","sourceHandles":["7103B","7103F","71040","71041","71042","71045","71046","71050","71075","71076","7109E","710A0","710A4","710A5","710A6","710A7","710A8","710B1","710B2","710B3","710B4","710B5","710B6","710B7","710B8","710BA","710BB","710BC","710BD","710C1","710C4","710C5","710C6","710CC","710CE","710D3","710D7","710D8","710D9","710DB","710DD","710E4","710E5","710EB","710F0","710F3","710F8","710FC","710FE","7110F","71111","71116","71142","71276","71285","7129B","712A1","712A3","712A9","712AC","71302","71306","7130B","7130F"],"partCount":1,"partsAreBOM":false,"status":"Submalla exacta; interpretación funcional y cotas parciales provisionales."} | {"boundingBoxM":{"min":[48.139687,72.04051,1.65],"max":[48.467928,72.354529,2.5]},"extentsM":[0.328241,0.314019,0.85],"meshSurfaceM2":1.150316,"meshVolumeM3":0.069849,"closedSolid":true,"basis":"Geometría de coordinación. Los volúmenes de referencia y subcomponentes no son cantidades de material ni componentes de fabricación certificados."} | {"documentId":"LHD2609-JG00100-20260904","title":"Cimentaciones y pedestales de equipos · revisión recibida 04/09/2026","date":"2026-09-04","sheet":"1 / 1-1","sourceHandles":["28C35","28C38","28C3B","28C89"]} | equipment | {"id":"equipment","name":"Equipos"} | {"profileId":"equipment_light_gray","name":"Equipo · gris claro provisional","materialName":"No especificado","physicalMaterialStatus":"unknown","physicalMaterialSource":"Sin especificación de material en la documentación revisada","appearanceStatus":"provisional","appearanceBasis":"Referencia visual de fotografías públicas de Jinhong Gas / fabricante. Apariencia provisional para coordinación; fotografías oficiales pueden orientar el color, pero no acreditan el material, el acabado ni el equipo concreto.","appearanceReferences":["jinhong-official-asu"],"note":"El perfil visual no confirma material, grado ni acabado del componente."} | {"status":"componente_independiente","note":"Objeto independiente seleccionable. Las caras se asignan una sola vez entre todos los componentes del conjunto.","parentEquipmentId":"AC1001A","isAssemblyIdentityCarrier":false} | {"elementId":"AC1001A--cad-region-013","ifcGuid":"2L110kTpjSBBTyf1K6Yuwf","ifcClass":"IfcBuildingElementProxy","buildingId":"process_plant","buildingName":"Planta de proceso","sourceDocumentId":"EQ-IMPLANTACION-20260430","sourceRepresentationKind":"equipmentComponent"} | {"layerId":"equipment","layerName":"Equipos","role":"Componente de equipo · cuerpo o accesorio","basis":"Clasificación por función del elemento; no modifica las especificaciones documentales."} | {"profileId":"equipment_light_gray","name":"Equipo · gris claro provisional","status":"provisional","basis":"Referencia visual de fotografías públicas de Jinhong Gas / fabricante. Apariencia provisional para coordinación; fotografías oficiales pueden orientar el color, pero no acreditan el material, el acabado ni el equipo concreto.","physicalMaterialUnchanged":true} | Equipos | No especificado | Equipos | Equipo · gris claro provisional | provisional | AC1001A--cad-region-013 | ["Componente separado de una reconstrucción documental del conjunto. Las alturas y detalles parciales conservan las limitaciones del fabricante registradas en parentEquipmentIssues.","Esta representación exterior no crea una chapa hueca ni añade componentes internos no documentados.","La pertenencia al conjunto no demuestra apoyo o anclaje directo a la cimentación."] | Geometría de coordinación. Los volúmenes de referencia y subcomponentes no son cantidades de material ni componentes de fabricación certificados. | Sin especificación de material en la documentación revisada | {"documentId":"EQ-IMPLANTACION-20260430","title":"Plano del fabricante: implantación de equipos","sheet":"LHD2609-GD01000 · espacio modelo","date":"2026-04-30","componentSourceHandles":["7103B","7103F","71040","71041","71042","71045","71046","71050","71075","71076","7109E","710A0","710A4","710A5","710A6","710A7","710A8","710B1","710B2","710B3","710B4","710B5","710B6","710B7","710B8","710BA","710BB","710BC","710BD","710C1","710C4","710C5","710C6","710CC","710CE","710D3","710D7","710D8","710D9","710DB","710DD","710E4","710E5","710EB","710F0","710F3","710F8","710FC","710FE","7110F","71111","71116","71142","71276","71285","7129B","712A1","712A3","712A9","712AC","71302","71306","7130B","7130F"]} | yes | equipment_light_gray | [0.88,0.89,0.88] | 0.45 | 0.28 | Referencia visual de fotografías públicas de Jinhong Gas / fabricante. Apariencia provisional para coordinación; fotografías oficiales pueden orientar el color, pero no acreditan el material, el acabado ni el equipo concreto. | La apariencia no certifica el material físico ni el acabado de fabricación. | BIM · Equipos | AC1001A | Compresor de aire AC1001A | IfcCompressor | {"documented":[{"label":"Dimensión X local del bastidor de referencia CAD","value":2.35,"unit":"m","source":"EQ-CARGAS-20260825 · contorno CAD · handles 3F3","status":"derivado"},{"label":"Dimensión Y local del bastidor de referencia CAD","value":5.22,"unit":"m","source":"EQ-CARGAS-20260825 · contorno CAD · handles 3F3","status":"derivado"},{"label":"Altura acotada","value":3.38,"unit":"m","source":"EQ-CARGAS-20260825 · handle 52E","status":"documentado"},{"label":"Cota relativa de la superficie de apoyo","value":0.4,"unit":"m","source":"LHD2609-JG00100-20260904 · sección 1 / 1-1 · 28C35, 28C38, 28C3B, 28C89","status":"documentado"}],"geometry":[{"label":"Extensión de la malla en X","value":3.1775829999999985,"unit":"m","source":"Geometría releída del IFC; datum absoluto de proceso provisional","status":"derivado"},{"label":"Extensión de la malla en Y","value":6.404527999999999,"unit":"m","source":"Geometría releída del IFC; datum absoluto de proceso provisional","status":"derivado"},{"label":"Extensión de la malla en Z","value":3.3800000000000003,"unit":"m","source":"Geometría releída del IFC; datum absoluto de proceso provisional","status":"derivado"},{"label":"Cota inferior de visualización","value":286.5,"unit":"m","source":"Geometría releída del IFC; datum absoluto de proceso provisional","status":"derivado"},{"label":"Cota superior de visualización","value":289.88,"unit":"m","source":"Geometría releída del IFC; datum absoluto de proceso provisional","status":"derivado"}],"notes":["Las extensiones de la malla se miden en los ejes del proyecto tras el giro de implantación; no sustituyen las dimensiones locales del fabricante.","La envolvente, su volumen y los espesores de visualización no son volúmenes de material ni cantidades de compra, construcción o fabricación.","Las dimensiones documentadas distinguen cotas explícitas y medidas extraídas de contornos CAD; las dimensiones geométricas describen únicamente la malla publicada.","Las extensiones de la malla refinada y las dimensiones documentadas del contorno o bastidor tienen distinto alcance; las cotas parciales del detalle son provisionales."]} | {"Estado de la planta":"Derivado del CAD y del giro de implantación","Nivel relativo del apoyo (m)":0.4,"Estado del nivel relativo":"Documentado en el plano de cimentaciones","Cero absoluto de visualización (m)":286.1,"Estado del cero absoluto":"Provisional","Cota del apoyo de visualización (m)":286.5,"Desplazamiento aplicado a la malla (m)":0.40000000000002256,"Criterio":"Nivel de apoyo relativo documentado. Se adopta el cero de proceso a 286,10 m solo para visualización; la equivalencia absoluta no está confirmada. No se añade un espesor de montaje sin cota del fabricante."} | ["La máquina está contenida en la envolvente de la cabina acústica; su superposición no acredita una interferencia física.","El bastidor CAD coincide con la referencia de 2,35 × 5,22 m del plano de cargas, pero cuerpos y auxiliares del detalle de abril sobresalen de esa referencia, hasta aproximadamente 1,048 m por el extremo sur y 0,246 m por el lado oeste. Extensión geométrica resultante: 2,595899 × 6,268101 × 3,38 m, derivada y pendiente de coordinación entre revisiones. Permanecen dentro de la cabina acústica. Compatibilidad de revisión pendiente de fabricante.","Todas las alturas parciales son hipótesis de visualización; solo la altura total de 3,38 m está acotada.","Las regiones del dibujo se usan como envolventes de cuerpos; la identificación funcional y la cota Z de cada pieza requieren verificación.","Pequeños taladros, tornillería y detalles interiores de las regiones no se extruyen como vacíos de fabricación.","El bastidor documentado mide 2,35 × 5,22 m. Los accesorios del detalle de abril sobresalen; el conjunto refinado ocupa aproximadamente 2,596 × 6,268 m en ejes del fabricante, pendiente de coordinación entre revisiones.","El acabado de grout HA-35 de 50 mm termina en +0,400; el hormigón termina en +0,350. La losa MAC contigua termina en +0,200.","El cero absoluto de la revisión no está definido; 286,10 m sigue siendo una hipótesis de coordinación.","Se alinea el punto inferior del conjunto del equipo, incluidos los pies ya representados, con la superficie de apoyo terminada; no se añade un espesor de calzos, placa o grout del fabricante no documentado."] | {"revision":"Detalle en planta de 2026-04-30 coordinado de forma preliminar con envolventes y alturas de 2026-08-25","status":"provisional","verticalRule":"Altura total documentada: 3,38 m. Plataforma gráfica de 0,15 m; los cuerpos extraídos de la planta reciben alturas provisionales entre 1,00 y 3,38 m, detalladas por subvolumen. No se dispone de alzado acotado de cada componente.","partCount":26,"source":{"documentId":"EQ-IMPLANTACION-20260430","title":"Plano del fabricante: implantación de equipos","sheet":"LHD2609-GD01000 · espacio modelo","date":"2026-04-30"},"heightSource":{"documentId":"EQ-CARGAS-20260825","title":"Plano del fabricante: cargas de equipos","sheet":"Espacio modelo","date":"2026-08-25"},"unconfirmedDimensions":["Todas las alturas parciales son hipótesis de visualización; solo la altura total de 3,38 m está acotada.","Las regiones del dibujo se usan como envolventes de cuerpos; la identificación funcional y la cota Z de cada pieza requieren verificación.","Pequeños taladros, tornillería y detalles interiores de las regiones no se extruyen como vacíos de fabricación."],"quantityUse":"Magnitudes de la geometría representada; no son cantidades de material, obra, compra, capacidad útil ni fabricación. En geometrías compuestas se suman superficies y volúmenes de partes y pueden existir solapes no depurados.","partsAreBOM":false} | equipment_component | {"min":[48.139687,70.121823,1.5],"max":[51.31727,76.526351,4.88]} | {"boundingBoxM":{"min":[48.139687,70.121823,1.5],"max":[51.31727,76.526351,4.88]},"extentsM":[3.1775829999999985,6.404527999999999,3.38],"meshSurfaceM2":165.1982435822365,"meshVolumeM3":20.17009895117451,"closedSolid":true,"windingConsistent":true,"basis":"Submalla exacta de los triángulos del modelo IFC coordinado; separación de componentes sin transformación ni retesselación."} | ["Todas las alturas parciales son hipótesis de visualización; solo la altura total de 3,38 m está acotada.","Las regiones del dibujo se usan como envolventes de cuerpos; la identificación funcional y la cota Z de cada pieza requieren verificación.","Pequeños taladros, tornillería y detalles interiores de las regiones no se extruyen como vacíos de fabricación.","La separación gráfica no aporta cotas de fabricación ni identifica piezas internas no documentadas.","Los materiales y acabados permanecen provisionales; las fotografías públicas solo orientan la apariencia."] | {"id":"AC1001A--cad-region-013","sourcePartId":"AC1001A--cad-region-013","name":"Cuerpo de equipo · región CAD 13","role":"equipment_component","classificationStatus":"provisional","classificationBasis":"Rol del subvolumen gráfico según el activo de detalle; identidad de fabricación no confirmada.","parentEquipmentId":"AC1001A","parentEquipmentGuid":"1ZhOcwnsbMzxhqtlvKa3pG","isAssemblyIdentityCarrier":false,"sourceFaceRange":[368,640],"sourceCurrentFaceIndices":[368,369,370,371,372,373,374,375,376,377,378,379,380,381,382,383,384,385,386,387,388,389,390,391,392,393,394,395,396,397,398,399,400,401,402,403,404,405,406,407,408,409,410,411,412,413,414,415,416,417,418,419,420,421,422,423,424,425,426,427,428,429,430,431,432,433,434,435,436,437,438,439,440,441,442,443,444,445,446,447,448,449,450,451,452,453,454,455,456,457,458,459,460,461,462,463,464,465,466,467,468,469,470,471,472,473,474,475,476,477,478,479,480,481,482,483,484,485,486,487,488,489,490,491,492,493,494,495,496,497,498,499,500,501,502,503,504,505,506,507,508,509,510,511,512,513,514,515,516,517,518,519,520,521,522,523,524,525,526,527,528,529,530,531,532,533,534,535,536,537,538,539,540,541,542,543,544,545,546,547,548,549,550,551,552,553,554,555,556,557,558,559,560,561,562,563,564,565,566,567,568,569,570,571,572,573,574,575,576,577,578,579,580,581,582,583,584,585,586,587,588,589,590,591,592,593,594,595,596,597,598,599,600,601,602,603,604,605,606,607,608,609,610,611,612,613,614,615,616,617,618,619,620,621,622,623,624,625,626,627,628,629,630,631,632,633,634,635,636,637,638,639],"sourceMeshSha256":"7b60c904c9d84d22fded9be34af09a09a9c198ec8e75e61902634d5e4064c761","sourceVertexIndices":[208,209,210,211,212,213,214,215,216,217,218,219,220,221,222,223,224,225,226,227,228,229,230,231,232,233,234,235,236,237,238,239,240,241,242,243,244,245,246,247,248,249,250,251,252,253,254,255,256,257,258,259,260,261,262,263,264,265,266,267,268,269,270,271,272,273,274,275,276,277,278,279,280,281,282,283,284,285,286,287,288,289,290,291,292,293,294,295,296,297,298,299,300,301,302,303,304,305,306,307,308,309,310,311,312,313,314,315,316,317,318,319,320,321,322,323,324,325,326,327,328,329,330,331,332,333,334,335,336,337,338,339,340,341,342,343,344,345],"separationMethod":"Partición exacta de triángulos existentes; coordenadas y orientación de caras conservadas.","quantityUse":"Magnitudes geométricas del subvolumen; no son cantidades netas de material, fabricación, suministro o capacidad."} | {"id":"AC1001A","name":"Compresor de aire AC1001A","relationship":"decomposed_component","parentShapeMeaning":"La forma del objeto que conserva el ID del equipo es únicamente su componente principal; el conjunto completo requiere sus hijos."} | {"kind":"through_parent","parentEquipmentId":"AC1001A","directAnchorageVerified":false,"note":"La relación del conjunto con cimentaciones se conserva en el objeto que mantiene el ID del equipo; no se atribuye fijación directa a cada subcomponente."} | Documento de implantación y apoyo del conjunto padre; no acredita fijación individual de este componente. | AC1001A--cad-region-013 | Cuerpo de equipo · región CAD 13 | Equipos | unknown | equipment_light_gray | {"documentId":"EQ-IMPLANTACION-20260430","title":"Plano del fabricante: implantación de equipos","sheet":"LHD2609-GD01000 · espacio modelo","date":"2026-04-30","componentSourceHandles":["7103B","7103F","71040","71041","71042","71045","71046","71050","71075","71076","7109E","710A0","710A4","710A5","710A6","710A7","710A8","710B1","710B2","710B3","710B4","710B5","710B6","710B7","710B8","710BA","710BB","710BC","710BD","710C1","710C4","710C5","710C6","710CC","710CE","710D3","710D7","710D8","710D9","710DB","710DD","710E4","710E5","710EB","710F0","710F3","710F8","710FC","710FE","7110F","71111","71116","71142","71276","71285","7129B","712A1","712A3","712A9","712AC","71302","71306","7130B","7130F"]} | Submalla de triángulos existentes; no hay nueva posición ni nuevas caras. | Cotas globales del conjunto conservadas aparte; las dimensiones de esta ficha son de la submalla. | Coordinación del conjunto padre; anclaje directo individual no acreditado. | Superficie y volumen geométricos brutos; no constituyen cantidades netas de obra, material o fabricación. | Plano general y dimensiones globales de AC1001A; no se asignan esas dimensiones globales a este componente. | ["7103B","7103F","71040","71041","71042","71045","71046","71050","71075","71076","7109E","710A0","710A4","710A5","710A6","710A7","710A8","710B1","710B2","710B3","710B4","710B5","710B6","710B7","710B8","710BA","710BB","710BC","710BD","710C1","710C4","710C5","710C6","710CC","710CE","710D3","710D7","710D8","710D9","710DB","710DD","710E4","710E5","710EB","710F0","710F3","710F8","710FC","710FE","7110F","71111","71116","71142","71276","71285","7129B","712A1","712A3","712A9","712AC","71302","71306","7130B","7130F"] | 1 | no | Submalla exacta; interpretación funcional y cotas parciales provisionales.
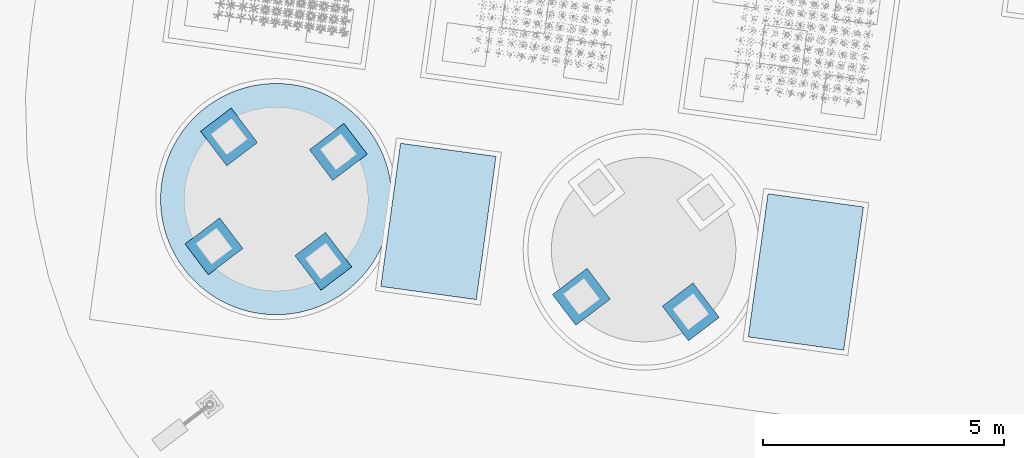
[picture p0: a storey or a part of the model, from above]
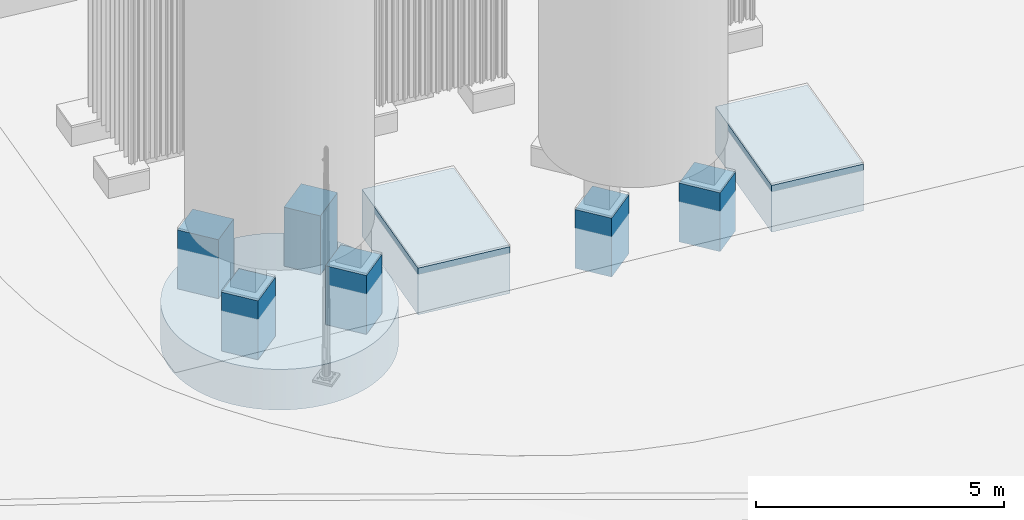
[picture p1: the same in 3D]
Properties of the parts of a building model (IFC4), part 29 of 134

# IfcBuildingElementProxy (140)
Name | Description | Document | Extensión de la malla en X (m) = ExtensionX (m) | Extensión de la malla en Y (m) = ExtensionY (m) | Extensión de la malla en Z (m) = ExtensionZ (m) | Cota inferior de visualización (m) | Cota superior de visualización (m) | SuperficieDeLaMalla (m2) | VolumenGeometrico (m3) | level | category = Categoria = Funcion | representationKind | material | dimensions | JH_InformacionBIM, source = DocumentoFuente | positioning = PosicionYEstado | issues | detailGeometry | geometryMetrics | installationSource | layerId = IdentificadorCapa | visualLayer | materialAppearance | componentSeparation | visualizationIdentity | classification | appearance | Disciplina | Material | Capa BIM = NombreCapa | Acabado de visualización = Acabado | Estado del acabado = Estado | Identificador | JH_Trazabilidad, IncidenciasPendientes | UsoDeLasMagnitudes | JH_EvidenciaDeMaterial, source | JH_DetalleGeometrico, source | VisibilidadInicial | Perfil | ColorRGB | Rugosidad | Metallicidad | Referencia | Nota | Group | parentEquipmentId = Identificador del equipo padre | parentEquipmentName = Equipo padre | parentEquipmentIfcClass | parentEquipmentDimensions | parentEquipmentPositioning | parentEquipmentIssues | parentEquipmentDetail | componentRole = Rol del componente | assemblyBBox | assemblyGeometryMetrics | manufacturerDetailsPending | component | assembly | foundationRelationship | installationSourceScope | Identificador del elemento = sourcePartId | Componente | Capa de visualización | Estado del material | Perfil visual del material | Fuente del componente | Criterio de partición | Criterio de las dimensiones | Relación con cimentaciones | Aplicabilidad de las mediciones | Referencia dimensional del conjunto | sourceHandles | partCount | partsAreBOM | status
Compresor de aire AC1001A · Cuerpo de equipo · región CAD 17 | Componente de equipo · cuerpo o accesorio | Plano del fabricante: implantación de equipos · referencia E7 | 0.535605 | 0.184588 | 2.6 | 286.65 | 289.25 | 3.70645 | 0.148968 | Apoyo relativo +0.400 m; cero absoluto provisional | Componente de equipo · cuerpo o accesorio | equipmentComponent | {"name":"No especificado","source":"Sin especificación de material en la documentación revisada","status":"unknown"} | {"documented":[{"label":"Referencia dimensional del conjunto","value":"Plano general y dimensiones globales de AC1001A; no se asignan esas dimensiones globales a este componente.","unit":"","source":"EQ-IMPLANTACION-20260430 · LHD2609-GD01000 · espacio modelo","status":"referencia_del_conjunto"}],"geometry":[{"label":"Extensión de la malla en X","value":0.5356050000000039,"unit":"m","source":"Geometría releída del IFC; datum absoluto de proceso provisional","status":"derivado"},{"label":"Extensión de la malla en Y","value":0.18458800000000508,"unit":"m","source":"Geometría releída del IFC; datum absoluto de proceso provisional","status":"derivado"},{"label":"Extensión de la malla en Z","value":2.6,"unit":"m","source":"Geometría releída del IFC; datum absoluto de proceso provisional","status":"derivado"},{"label":"Cota inferior de visualización","value":286.65,"unit":"m","source":"Geometría releída del IFC; datum absoluto de proceso provisional","status":"derivado"},{"label":"Cota superior de visualización","value":289.25,"unit":"m","source":"Geometría releída del IFC; datum absoluto de proceso provisional","status":"derivado"}],"notes":["Las dimensiones del equipo completo se conservan en parentEquipmentDimensions.","Las extensiones en X/Y son de los ejes del modelo y no sustituyen cotas locales de fabricación.","No se infieren espesores de chapa, tolerancias ni dimensiones de piezas a partir de la partición."]} | {"documentId":"EQ-IMPLANTACION-20260430","title":"Plano del fabricante: implantación de equipos","sheet":"LHD2609-GD01000 · espacio modelo","date":"2026-04-30","componentSourceHandles":["7134C","71A0B","71A0C","71A0F","71A10","71A11","71A17","71A68","72D35","72D38"]} | {"horizontalStatus":"derivado_del_conjunto","verticalStatus":"derivado_del_conjunto","coordinateSystem":"model_local_m","parentEquipmentId":"AC1001A","transformApplied":false,"note":"Coordenadas copiadas exactamente del equipo coordinado; no se ha movido, girado, elevado ni reescalado este componente.","foundationRelationship":"El apoyo y las cotas de instalación se documentan para el conjunto padre. Esta submalla no acredita un anclaje directo.","meshMinimumAbsoluteElevationM":286.65,"assemblyPlacementField":"parentEquipmentPositioning"} | ["Componente separado de una reconstrucción documental del conjunto. Las alturas y detalles parciales conservan las limitaciones del fabricante registradas en parentEquipmentIssues.","Esta representación exterior no crea una chapa hueca ni añade componentes internos no documentados.","La pertenencia al conjunto no demuestra apoyo o anclaje directo a la cimentación."] | {"source":{"documentId":"EQ-IMPLANTACION-20260430","title":"Plano del fabricante: implantación de equipos","sheet":"LHD2609-GD01000 · espacio modelo","date":"2026-04-30","componentSourceHandles":["7134C","71A0B","71A0C","71A0F","71A10","71A11","71A17","71A68","72D35","72D38"]},"sourcePartId":"AC1001A--cad-region-017","sourceHandles":["7134C","71A0B","71A0C","71A0F","71A10","71A11","71A17","71A68","72D35","72D38"],"partCount":1,"partsAreBOM":false,"status":"Submalla exacta; interpretación funcional y cotas parciales provisionales."} | {"boundingBoxM":{"min":[49.551866,75.239374,1.65],"max":[50.087471,75.423962,4.25]},"extentsM":[0.535605,0.184588,2.6],"meshSurfaceM2":3.706453,"meshVolumeM3":0.148968,"closedSolid":true,"basis":"Geometría de coordinación. Los volúmenes de referencia y subcomponentes no son cantidades de material ni componentes de fabricación certificados."} | {"documentId":"LHD2609-JG00100-20260904","title":"Cimentaciones y pedestales de equipos · revisión recibida 04/09/2026","date":"2026-09-04","sheet":"1 / 1-1","sourceHandles":["28C35","28C38","28C3B","28C89"]} | equipment | {"id":"equipment","name":"Equipos"} | {"profileId":"equipment_light_gray","name":"Equipo · gris claro provisional","materialName":"No especificado","physicalMaterialStatus":"unknown","physicalMaterialSource":"Sin especificación de material en la documentación revisada","appearanceStatus":"provisional","appearanceBasis":"Referencia visual de fotografías públicas de Jinhong Gas / fabricante. Apariencia provisional para coordinación; fotografías oficiales pueden orientar el color, pero no acreditan el material, el acabado ni el equipo concreto.","appearanceReferences":["jinhong-official-asu"],"note":"El perfil visual no confirma material, grado ni acabado del componente."} | {"status":"componente_independiente","note":"Objeto independiente seleccionable. Las caras se asignan una sola vez entre todos los componentes del conjunto.","parentEquipmentId":"AC1001A","isAssemblyIdentityCarrier":false} | {"elementId":"AC1001A--cad-region-017","ifcGuid":"1orqYQnZnVpRq7QCFVtpN2","ifcClass":"IfcBuildingElementProxy","buildingId":"process_plant","buildingName":"Planta de proceso","sourceDocumentId":"EQ-IMPLANTACION-20260430","sourceRepresentationKind":"equipmentComponent"} | {"layerId":"equipment","layerName":"Equipos","role":"Componente de equipo · cuerpo o accesorio","basis":"Clasificación por función del elemento; no modifica las especificaciones documentales."} | {"profileId":"equipment_light_gray","name":"Equipo · gris claro provisional","status":"provisional","basis":"Referencia visual de fotografías públicas de Jinhong Gas / fabricante. Apariencia provisional para coordinación; fotografías oficiales pueden orientar el color, pero no acreditan el material, el acabado ni el equipo concreto.","physicalMaterialUnchanged":true} | Equipos | No especificado | Equipos | Equipo · gris claro provisional | provisional | AC1001A--cad-region-017 | ["Componente separado de una reconstrucción documental del conjunto. Las alturas y detalles parciales conservan las limitaciones del fabricante registradas en parentEquipmentIssues.","Esta representación exterior no crea una chapa hueca ni añade componentes internos no documentados.","La pertenencia al conjunto no demuestra apoyo o anclaje directo a la cimentación."] | Geometría de coordinación. Los volúmenes de referencia y subcomponentes no son cantidades de material ni componentes de fabricación certificados. | Sin especificación de material en la documentación revisada | {"documentId":"EQ-IMPLANTACION-20260430","title":"Plano del fabricante: implantación de equipos","sheet":"LHD2609-GD01000 · espacio modelo","date":"2026-04-30","componentSourceHandles":["7134C","71A0B","71A0C","71A0F","71A10","71A11","71A17","71A68","72D35","72D38"]} | yes | equipment_light_gray | [0.88,0.89,0.88] | 0.45 | 0.28 | Referencia visual de fotografías públicas de Jinhong Gas / fabricante. Apariencia provisional para coordinación; fotografías oficiales pueden orientar el color, pero no acreditan el material, el acabado ni el equipo concreto. | La apariencia no certifica el material físico ni el acabado de fabricación. | BIM · Equipos | AC1001A | Compresor de aire AC1001A | IfcCompressor | {"documented":[{"label":"Dimensión X local del bastidor de referencia CAD","value":2.35,"unit":"m","source":"EQ-CARGAS-20260825 · contorno CAD · handles 3F3","status":"derivado"},{"label":"Dimensión Y local del bastidor de referencia CAD","value":5.22,"unit":"m","source":"EQ-CARGAS-20260825 · contorno CAD · handles 3F3","status":"derivado"},{"label":"Altura acotada","value":3.38,"unit":"m","source":"EQ-CARGAS-20260825 · handle 52E","status":"documentado"},{"label":"Cota relativa de la superficie de apoyo","value":0.4,"unit":"m","source":"LHD2609-JG00100-20260904 · sección 1 / 1-1 · 28C35, 28C38, 28C3B, 28C89","status":"documentado"}],"geometry":[{"label":"Extensión de la malla en X","value":3.1775829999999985,"unit":"m","source":"Geometría releída del IFC; datum absoluto de proceso provisional","status":"derivado"},{"label":"Extensión de la malla en Y","value":6.404527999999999,"unit":"m","source":"Geometría releída del IFC; datum absoluto de proceso provisional","status":"derivado"},{"label":"Extensión de la malla en Z","value":3.3800000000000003,"unit":"m","source":"Geometría releída del IFC; datum absoluto de proceso provisional","status":"derivado"},{"label":"Cota inferior de visualización","value":286.5,"unit":"m","source":"Geometría releída del IFC; datum absoluto de proceso provisional","status":"derivado"},{"label":"Cota superior de visualización","value":289.88,"unit":"m","source":"Geometría releída del IFC; datum absoluto de proceso provisional","status":"derivado"}],"notes":["Las extensiones de la malla se miden en los ejes del proyecto tras el giro de implantación; no sustituyen las dimensiones locales del fabricante.","La envolvente, su volumen y los espesores de visualización no son volúmenes de material ni cantidades de compra, construcción o fabricación.","Las dimensiones documentadas distinguen cotas explícitas y medidas extraídas de contornos CAD; las dimensiones geométricas describen únicamente la malla publicada.","Las extensiones de la malla refinada y las dimensiones documentadas del contorno o bastidor tienen distinto alcance; las cotas parciales del detalle son provisionales."]} | {"Estado de la planta":"Derivado del CAD y del giro de implantación","Nivel relativo del apoyo (m)":0.4,"Estado del nivel relativo":"Documentado en el plano de cimentaciones","Cero absoluto de visualización (m)":286.1,"Estado del cero absoluto":"Provisional","Cota del apoyo de visualización (m)":286.5,"Desplazamiento aplicado a la malla (m)":0.40000000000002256,"Criterio":"Nivel de apoyo relativo documentado. Se adopta el cero de proceso a 286,10 m solo para visualización; la equivalencia absoluta no está confirmada. No se añade un espesor de montaje sin cota del fabricante."} | ["La máquina está contenida en la envolvente de la cabina acústica; su superposición no acredita una interferencia física.","El bastidor CAD coincide con la referencia de 2,35 × 5,22 m del plano de cargas, pero cuerpos y auxiliares del detalle de abril sobresalen de esa referencia, hasta aproximadamente 1,048 m por el extremo sur y 0,246 m por el lado oeste. Extensión geométrica resultante: 2,595899 × 6,268101 × 3,38 m, derivada y pendiente de coordinación entre revisiones. Permanecen dentro de la cabina acústica. Compatibilidad de revisión pendiente de fabricante.","Todas las alturas parciales son hipótesis de visualización; solo la altura total de 3,38 m está acotada.","Las regiones del dibujo se usan como envolventes de cuerpos; la identificación funcional y la cota Z de cada pieza requieren verificación.","Pequeños taladros, tornillería y detalles interiores de las regiones no se extruyen como vacíos de fabricación.","El bastidor documentado mide 2,35 × 5,22 m. Los accesorios del detalle de abril sobresalen; el conjunto refinado ocupa aproximadamente 2,596 × 6,268 m en ejes del fabricante, pendiente de coordinación entre revisiones.","El acabado de grout HA-35 de 50 mm termina en +0,400; el hormigón termina en +0,350. La losa MAC contigua termina en +0,200.","El cero absoluto de la revisión no está definido; 286,10 m sigue siendo una hipótesis de coordinación.","Se alinea el punto inferior del conjunto del equipo, incluidos los pies ya representados, con la superficie de apoyo terminada; no se añade un espesor de calzos, placa o grout del fabricante no documentado."] | {"revision":"Detalle en planta de 2026-04-30 coordinado de forma preliminar con envolventes y alturas de 2026-08-25","status":"provisional","verticalRule":"Altura total documentada: 3,38 m. Plataforma gráfica de 0,15 m; los cuerpos extraídos de la planta reciben alturas provisionales entre 1,00 y 3,38 m, detalladas por subvolumen. No se dispone de alzado acotado de cada componente.","partCount":26,"source":{"documentId":"EQ-IMPLANTACION-20260430","title":"Plano del fabricante: implantación de equipos","sheet":"LHD2609-GD01000 · espacio modelo","date":"2026-04-30"},"heightSource":{"documentId":"EQ-CARGAS-20260825","title":"Plano del fabricante: cargas de equipos","sheet":"Espacio modelo","date":"2026-08-25"},"unconfirmedDimensions":["Todas las alturas parciales son hipótesis de visualización; solo la altura total de 3,38 m está acotada.","Las regiones del dibujo se usan como envolventes de cuerpos; la identificación funcional y la cota Z de cada pieza requieren verificación.","Pequeños taladros, tornillería y detalles interiores de las regiones no se extruyen como vacíos de fabricación."],"quantityUse":"Magnitudes de la geometría representada; no son cantidades de material, obra, compra, capacidad útil ni fabricación. En geometrías compuestas se suman superficies y volúmenes de partes y pueden existir solapes no depurados.","partsAreBOM":false} | equipment_component | {"min":[48.139687,70.121823,1.5],"max":[51.31727,76.526351,4.88]} | {"boundingBoxM":{"min":[48.139687,70.121823,1.5],"max":[51.31727,76.526351,4.88]},"extentsM":[3.1775829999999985,6.404527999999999,3.38],"meshSurfaceM2":165.1982435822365,"meshVolumeM3":20.17009895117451,"closedSolid":true,"windingConsistent":true,"basis":"Submalla exacta de los triángulos del modelo IFC coordinado; separación de componentes sin transformación ni retesselación."} | ["Todas las alturas parciales son hipótesis de visualización; solo la altura total de 3,38 m está acotada.","Las regiones del dibujo se usan como envolventes de cuerpos; la identificación funcional y la cota Z de cada pieza requieren verificación.","Pequeños taladros, tornillería y detalles interiores de las regiones no se extruyen como vacíos de fabricación.","La separación gráfica no aporta cotas de fabricación ni identifica piezas internas no documentadas.","Los materiales y acabados permanecen provisionales; las fotografías públicas solo orientan la apariencia."] | {"id":"AC1001A--cad-region-017","sourcePartId":"AC1001A--cad-region-017","name":"Cuerpo de equipo · región CAD 17","role":"equipment_component","classificationStatus":"provisional","classificationBasis":"Rol del subvolumen gráfico según el activo de detalle; identidad de fabricación no confirmada.","parentEquipmentId":"AC1001A","parentEquipmentGuid":"1ZhOcwnsbMzxhqtlvKa3pG","isAssemblyIdentityCarrier":false,"sourceFaceRange":[1256,1348],"sourceCurrentFaceIndices":[1256,1257,1258,1259,1260,1261,1262,1263,1264,1265,1266,1267,1268,1269,1270,1271,1272,1273,1274,1275,1276,1277,1278,1279,1280,1281,1282,1283,1284,1285,1286,1287,1288,1289,1290,1291,1292,1293,1294,1295,1296,1297,1298,1299,1300,1301,1302,1303,1304,1305,1306,1307,1308,1309,1310,1311,1312,1313,1314,1315,1316,1317,1318,1319,1320,1321,1322,1323,1324,1325,1326,1327,1328,1329,1330,1331,1332,1333,1334,1335,1336,1337,1338,1339,1340,1341,1342,1343,1344,1345,1346,1347],"sourceMeshSha256":"7b60c904c9d84d22fded9be34af09a09a9c198ec8e75e61902634d5e4064c761","sourceVertexIndices":[658,659,660,661,662,663,664,665,666,667,668,669,670,671,672,673,674,675,676,677,678,679,680,681,682,683,684,685,686,687,688,689,690,691,692,693,694,695,696,697,698,699,700,701,702,703,704,705],"separationMethod":"Partición exacta de triángulos existentes; coordenadas y orientación de caras conservadas.","quantityUse":"Magnitudes geométricas del subvolumen; no son cantidades netas de material, fabricación, suministro o capacidad."} | {"id":"AC1001A","name":"Compresor de aire AC1001A","relationship":"decomposed_component","parentShapeMeaning":"La forma del objeto que conserva el ID del equipo es únicamente su componente principal; el conjunto completo requiere sus hijos."} | {"kind":"through_parent","parentEquipmentId":"AC1001A","directAnchorageVerified":false,"note":"La relación del conjunto con cimentaciones se conserva en el objeto que mantiene el ID del equipo; no se atribuye fijación directa a cada subcomponente."} | Documento de implantación y apoyo del conjunto padre; no acredita fijación individual de este componente. | AC1001A--cad-region-017 | Cuerpo de equipo · región CAD 17 | Equipos | unknown | equipment_light_gray | {"documentId":"EQ-IMPLANTACION-20260430","title":"Plano del fabricante: implantación de equipos","sheet":"LHD2609-GD01000 · espacio modelo","date":"2026-04-30","componentSourceHandles":["7134C","71A0B","71A0C","71A0F","71A10","71A11","71A17","71A68","72D35","72D38"]} | Submalla de triángulos existentes; no hay nueva posición ni nuevas caras. | Cotas globales del conjunto conservadas aparte; las dimensiones de esta ficha son de la submalla. | Coordinación del conjunto padre; anclaje directo individual no acreditado. | Superficie y volumen geométricos brutos; no constituyen cantidades netas de obra, material o fabricación. | Plano general y dimensiones globales de AC1001A; no se asignan esas dimensiones globales a este componente. | ["7134C","71A0B","71A0C","71A0F","71A10","71A11","71A17","71A68","72D35","72D38"] | 1 | no | Submalla exacta; interpretación funcional y cotas parciales provisionales.
Compresor de aire AC1001A · Cuerpo de equipo · región CAD 18 | Componente de equipo · cuerpo o accesorio | Plano del fabricante: implantación de equipos · referencia E7 | 1.15721 | 0.202982 | 2.6 | 286.65 | 289.25 | 6.31478 | 0.147819 | Apoyo relativo +0.400 m; cero absoluto provisional | Componente de equipo · cuerpo o accesorio | equipmentComponent | {"name":"No especificado","source":"Sin especificación de material en la documentación revisada","status":"unknown"} | {"documented":[{"label":"Referencia dimensional del conjunto","value":"Plano general y dimensiones globales de AC1001A; no se asignan esas dimensiones globales a este componente.","unit":"","source":"EQ-IMPLANTACION-20260430 · LHD2609-GD01000 · espacio modelo","status":"referencia_del_conjunto"}],"geometry":[{"label":"Extensión de la malla en X","value":1.1572139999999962,"unit":"m","source":"Geometría releída del IFC; datum absoluto de proceso provisional","status":"derivado"},{"label":"Extensión de la malla en Y","value":0.20298199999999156,"unit":"m","source":"Geometría releída del IFC; datum absoluto de proceso provisional","status":"derivado"},{"label":"Extensión de la malla en Z","value":2.6,"unit":"m","source":"Geometría releída del IFC; datum absoluto de proceso provisional","status":"derivado"},{"label":"Cota inferior de visualización","value":286.65,"unit":"m","source":"Geometría releída del IFC; datum absoluto de proceso provisional","status":"derivado"},{"label":"Cota superior de visualización","value":289.25,"unit":"m","source":"Geometría releída del IFC; datum absoluto de proceso provisional","status":"derivado"}],"notes":["Las dimensiones del equipo completo se conservan en parentEquipmentDimensions.","Las extensiones en X/Y son de los ejes del modelo y no sustituyen cotas locales de fabricación.","No se infieren espesores de chapa, tolerancias ni dimensiones de piezas a partir de la partición."]} | {"documentId":"EQ-IMPLANTACION-20260430","title":"Plano del fabricante: implantación de equipos","sheet":"LHD2609-GD01000 · espacio modelo","date":"2026-04-30","componentSourceHandles":["7134C","72C0A","72D2E","72D32","72D34","72D35","72D36"]} | {"horizontalStatus":"derivado_del_conjunto","verticalStatus":"derivado_del_conjunto","coordinateSystem":"model_local_m","parentEquipmentId":"AC1001A","transformApplied":false,"note":"Coordenadas copiadas exactamente del equipo coordinado; no se ha movido, girado, elevado ni reescalado este componente.","foundationRelationship":"El apoyo y las cotas de instalación se documentan para el conjunto padre. Esta submalla no acredita un anclaje directo.","meshMinimumAbsoluteElevationM":286.65,"assemblyPlacementField":"parentEquipmentPositioning"} | ["Componente separado de una reconstrucción documental del conjunto. Las alturas y detalles parciales conservan las limitaciones del fabricante registradas en parentEquipmentIssues.","Esta representación exterior no crea una chapa hueca ni añade componentes internos no documentados.","La pertenencia al conjunto no demuestra apoyo o anclaje directo a la cimentación."] | {"source":{"documentId":"EQ-IMPLANTACION-20260430","title":"Plano del fabricante: implantación de equipos","sheet":"LHD2609-GD01000 · espacio modelo","date":"2026-04-30","componentSourceHandles":["7134C","72C0A","72D2E","72D32","72D34","72D35","72D36"]},"sourcePartId":"AC1001A--cad-region-018","sourceHandles":["7134C","72C0A","72D2E","72D32","72D34","72D35","72D36"],"partCount":1,"partsAreBOM":false,"status":"Submalla exacta; interpretación funcional y cotas parciales provisionales."} | {"boundingBoxM":{"min":[49.108417,75.3978,1.65],"max":[50.265631,75.600782,4.25]},"extentsM":[1.157214,0.202982,2.6],"meshSurfaceM2":6.314784,"meshVolumeM3":0.147819,"closedSolid":true,"basis":"Geometría de coordinación. Los volúmenes de referencia y subcomponentes no son cantidades de material ni componentes de fabricación certificados."} | {"documentId":"LHD2609-JG00100-20260904","title":"Cimentaciones y pedestales de equipos · revisión recibida 04/09/2026","date":"2026-09-04","sheet":"1 / 1-1","sourceHandles":["28C35","28C38","28C3B","28C89"]} | equipment | {"id":"equipment","name":"Equipos"} | {"profileId":"equipment_light_gray","name":"Equipo · gris claro provisional","materialName":"No especificado","physicalMaterialStatus":"unknown","physicalMaterialSource":"Sin especificación de material en la documentación revisada","appearanceStatus":"provisional","appearanceBasis":"Referencia visual de fotografías públicas de Jinhong Gas / fabricante. Apariencia provisional para coordinación; fotografías oficiales pueden orientar el color, pero no acreditan el material, el acabado ni el equipo concreto.","appearanceReferences":["jinhong-official-asu"],"note":"El perfil visual no confirma material, grado ni acabado del componente."} | {"status":"componente_independiente","note":"Objeto independiente seleccionable. Las caras se asignan una sola vez entre todos los componentes del conjunto.","parentEquipmentId":"AC1001A","isAssemblyIdentityCarrier":false} | {"elementId":"AC1001A--cad-region-018","ifcGuid":"2DCcD9IXnO1O5CQgo4lhGD","ifcClass":"IfcBuildingElementProxy","buildingId":"process_plant","buildingName":"Planta de proceso","sourceDocumentId":"EQ-IMPLANTACION-20260430","sourceRepresentationKind":"equipmentComponent"} | {"layerId":"equipment","layerName":"Equipos","role":"Componente de equipo · cuerpo o accesorio","basis":"Clasificación por función del elemento; no modifica las especificaciones documentales."} | {"profileId":"equipment_light_gray","name":"Equipo · gris claro provisional","status":"provisional","basis":"Referencia visual de fotografías públicas de Jinhong Gas / fabricante. Apariencia provisional para coordinación; fotografías oficiales pueden orientar el color, pero no acreditan el material, el acabado ni el equipo concreto.","physicalMaterialUnchanged":true} | Equipos | No especificado | Equipos | Equipo · gris claro provisional | provisional | AC1001A--cad-region-018 | ["Componente separado de una reconstrucción documental del conjunto. Las alturas y detalles parciales conservan las limitaciones del fabricante registradas en parentEquipmentIssues.","Esta representación exterior no crea una chapa hueca ni añade componentes internos no documentados.","La pertenencia al conjunto no demuestra apoyo o anclaje directo a la cimentación."] | Geometría de coordinación. Los volúmenes de referencia y subcomponentes no son cantidades de material ni componentes de fabricación certificados. | Sin especificación de material en la documentación revisada | {"documentId":"EQ-IMPLANTACION-20260430","title":"Plano del fabricante: implantación de equipos","sheet":"LHD2609-GD01000 · espacio modelo","date":"2026-04-30","componentSourceHandles":["7134C","72C0A","72D2E","72D32","72D34","72D35","72D36"]} | yes | equipment_light_gray | [0.88,0.89,0.88] | 0.45 | 0.28 | Referencia visual de fotografías públicas de Jinhong Gas / fabricante. Apariencia provisional para coordinación; fotografías oficiales pueden orientar el color, pero no acreditan el material, el acabado ni el equipo concreto. | La apariencia no certifica el material físico ni el acabado de fabricación. | BIM · Equipos | AC1001A | Compresor de aire AC1001A | IfcCompressor | {"documented":[{"label":"Dimensión X local del bastidor de referencia CAD","value":2.35,"unit":"m","source":"EQ-CARGAS-20260825 · contorno CAD · handles 3F3","status":"derivado"},{"label":"Dimensión Y local del bastidor de referencia CAD","value":5.22,"unit":"m","source":"EQ-CARGAS-20260825 · contorno CAD · handles 3F3","status":"derivado"},{"label":"Altura acotada","value":3.38,"unit":"m","source":"EQ-CARGAS-20260825 · handle 52E","status":"documentado"},{"label":"Cota relativa de la superficie de apoyo","value":0.4,"unit":"m","source":"LHD2609-JG00100-20260904 · sección 1 / 1-1 · 28C35, 28C38, 28C3B, 28C89","status":"documentado"}],"geometry":[{"label":"Extensión de la malla en X","value":3.1775829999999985,"unit":"m","source":"Geometría releída del IFC; datum absoluto de proceso provisional","status":"derivado"},{"label":"Extensión de la malla en Y","value":6.404527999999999,"unit":"m","source":"Geometría releída del IFC; datum absoluto de proceso provisional","status":"derivado"},{"label":"Extensión de la malla en Z","value":3.3800000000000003,"unit":"m","source":"Geometría releída del IFC; datum absoluto de proceso provisional","status":"derivado"},{"label":"Cota inferior de visualización","value":286.5,"unit":"m","source":"Geometría releída del IFC; datum absoluto de proceso provisional","status":"derivado"},{"label":"Cota superior de visualización","value":289.88,"unit":"m","source":"Geometría releída del IFC; datum absoluto de proceso provisional","status":"derivado"}],"notes":["Las extensiones de la malla se miden en los ejes del proyecto tras el giro de implantación; no sustituyen las dimensiones locales del fabricante.","La envolvente, su volumen y los espesores de visualización no son volúmenes de material ni cantidades de compra, construcción o fabricación.","Las dimensiones documentadas distinguen cotas explícitas y medidas extraídas de contornos CAD; las dimensiones geométricas describen únicamente la malla publicada.","Las extensiones de la malla refinada y las dimensiones documentadas del contorno o bastidor tienen distinto alcance; las cotas parciales del detalle son provisionales."]} | {"Estado de la planta":"Derivado del CAD y del giro de implantación","Nivel relativo del apoyo (m)":0.4,"Estado del nivel relativo":"Documentado en el plano de cimentaciones","Cero absoluto de visualización (m)":286.1,"Estado del cero absoluto":"Provisional","Cota del apoyo de visualización (m)":286.5,"Desplazamiento aplicado a la malla (m)":0.40000000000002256,"Criterio":"Nivel de apoyo relativo documentado. Se adopta el cero de proceso a 286,10 m solo para visualización; la equivalencia absoluta no está confirmada. No se añade un espesor de montaje sin cota del fabricante."} | ["La máquina está contenida en la envolvente de la cabina acústica; su superposición no acredita una interferencia física.","El bastidor CAD coincide con la referencia de 2,35 × 5,22 m del plano de cargas, pero cuerpos y auxiliares del detalle de abril sobresalen de esa referencia, hasta aproximadamente 1,048 m por el extremo sur y 0,246 m por el lado oeste. Extensión geométrica resultante: 2,595899 × 6,268101 × 3,38 m, derivada y pendiente de coordinación entre revisiones. Permanecen dentro de la cabina acústica. Compatibilidad de revisión pendiente de fabricante.","Todas las alturas parciales son hipótesis de visualización; solo la altura total de 3,38 m está acotada.","Las regiones del dibujo se usan como envolventes de cuerpos; la identificación funcional y la cota Z de cada pieza requieren verificación.","Pequeños taladros, tornillería y detalles interiores de las regiones no se extruyen como vacíos de fabricación.","El bastidor documentado mide 2,35 × 5,22 m. Los accesorios del detalle de abril sobresalen; el conjunto refinado ocupa aproximadamente 2,596 × 6,268 m en ejes del fabricante, pendiente de coordinación entre revisiones.","El acabado de grout HA-35 de 50 mm termina en +0,400; el hormigón termina en +0,350. La losa MAC contigua termina en +0,200.","El cero absoluto de la revisión no está definido; 286,10 m sigue siendo una hipótesis de coordinación.","Se alinea el punto inferior del conjunto del equipo, incluidos los pies ya representados, con la superficie de apoyo terminada; no se añade un espesor de calzos, placa o grout del fabricante no documentado."] | {"revision":"Detalle en planta de 2026-04-30 coordinado de forma preliminar con envolventes y alturas de 2026-08-25","status":"provisional","verticalRule":"Altura total documentada: 3,38 m. Plataforma gráfica de 0,15 m; los cuerpos extraídos de la planta reciben alturas provisionales entre 1,00 y 3,38 m, detalladas por subvolumen. No se dispone de alzado acotado de cada componente.","partCount":26,"source":{"documentId":"EQ-IMPLANTACION-20260430","title":"Plano del fabricante: implantación de equipos","sheet":"LHD2609-GD01000 · espacio modelo","date":"2026-04-30"},"heightSource":{"documentId":"EQ-CARGAS-20260825","title":"Plano del fabricante: cargas de equipos","sheet":"Espacio modelo","date":"2026-08-25"},"unconfirmedDimensions":["Todas las alturas parciales son hipótesis de visualización; solo la altura total de 3,38 m está acotada.","Las regiones del dibujo se usan como envolventes de cuerpos; la identificación funcional y la cota Z de cada pieza requieren verificación.","Pequeños taladros, tornillería y detalles interiores de las regiones no se extruyen como vacíos de fabricación."],"quantityUse":"Magnitudes de la geometría representada; no son cantidades de material, obra, compra, capacidad útil ni fabricación. En geometrías compuestas se suman superficies y volúmenes de partes y pueden existir solapes no depurados.","partsAreBOM":false} | equipment_component | {"min":[48.139687,70.121823,1.5],"max":[51.31727,76.526351,4.88]} | {"boundingBoxM":{"min":[48.139687,70.121823,1.5],"max":[51.31727,76.526351,4.88]},"extentsM":[3.1775829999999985,6.404527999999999,3.38],"meshSurfaceM2":165.1982435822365,"meshVolumeM3":20.17009895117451,"closedSolid":true,"windingConsistent":true,"basis":"Submalla exacta de los triángulos del modelo IFC coordinado; separación de componentes sin transformación ni retesselación."} | ["Todas las alturas parciales son hipótesis de visualización; solo la altura total de 3,38 m está acotada.","Las regiones del dibujo se usan como envolventes de cuerpos; la identificación funcional y la cota Z de cada pieza requieren verificación.","Pequeños taladros, tornillería y detalles interiores de las regiones no se extruyen como vacíos de fabricación.","La separación gráfica no aporta cotas de fabricación ni identifica piezas internas no documentadas.","Los materiales y acabados permanecen provisionales; las fotografías públicas solo orientan la apariencia."] | {"id":"AC1001A--cad-region-018","sourcePartId":"AC1001A--cad-region-018","name":"Cuerpo de equipo · región CAD 18","role":"equipment_component","classificationStatus":"provisional","classificationBasis":"Rol del subvolumen gráfico según el activo de detalle; identidad de fabricación no confirmada.","parentEquipmentId":"AC1001A","parentEquipmentGuid":"1ZhOcwnsbMzxhqtlvKa3pG","isAssemblyIdentityCarrier":false,"sourceFaceRange":[1348,1360],"sourceCurrentFaceIndices":[1348,1349,1350,1351,1352,1353,1354,1355,1356,1357,1358,1359],"sourceMeshSha256":"7b60c904c9d84d22fded9be34af09a09a9c198ec8e75e61902634d5e4064c761","sourceVertexIndices":[706,707,708,709,710,711,712,713],"separationMethod":"Partición exacta de triángulos existentes; coordenadas y orientación de caras conservadas.","quantityUse":"Magnitudes geométricas del subvolumen; no son cantidades netas de material, fabricación, suministro o capacidad."} | {"id":"AC1001A","name":"Compresor de aire AC1001A","relationship":"decomposed_component","parentShapeMeaning":"La forma del objeto que conserva el ID del equipo es únicamente su componente principal; el conjunto completo requiere sus hijos."} | {"kind":"through_parent","parentEquipmentId":"AC1001A","directAnchorageVerified":false,"note":"La relación del conjunto con cimentaciones se conserva en el objeto que mantiene el ID del equipo; no se atribuye fijación directa a cada subcomponente."} | Documento de implantación y apoyo del conjunto padre; no acredita fijación individual de este componente. | AC1001A--cad-region-018 | Cuerpo de equipo · región CAD 18 | Equipos | unknown | equipment_light_gray | {"documentId":"EQ-IMPLANTACION-20260430","title":"Plano del fabricante: implantación de equipos","sheet":"LHD2609-GD01000 · espacio modelo","date":"2026-04-30","componentSourceHandles":["7134C","72C0A","72D2E","72D32","72D34","72D35","72D36"]} | Submalla de triángulos existentes; no hay nueva posición ni nuevas caras. | Cotas globales del conjunto conservadas aparte; las dimensiones de esta ficha son de la submalla. | Coordinación del conjunto padre; anclaje directo individual no acreditado. | Superficie y volumen geométricos brutos; no constituyen cantidades netas de obra, material o fabricación. | Plano general y dimensiones globales de AC1001A; no se asignan esas dimensiones globales a este componente. | ["7134C","72C0A","72D2E","72D32","72D34","72D35","72D36"] | 1 | no | Submalla exacta; interpretación funcional y cotas parciales provisionales.
Compresor de aire AC1001A · Cuerpo de equipo · región CAD 19 | Componente de equipo · cuerpo o accesorio | Plano del fabricante: implantación de equipos · referencia E7 | 0.373734 | 0.205147 | 2.6 | 286.65 | 289.25 | 2.78372 | 0.146224 | Apoyo relativo +0.400 m; cero absoluto provisional | Componente de equipo · cuerpo o accesorio | equipmentComponent | {"name":"No especificado","source":"Sin especificación de material en la documentación revisada","status":"unknown"} | {"documented":[{"label":"Referencia dimensional del conjunto","value":"Plano general y dimensiones globales de AC1001A; no se asignan esas dimensiones globales a este componente.","unit":"","source":"EQ-IMPLANTACION-20260430 · LHD2609-GD01000 · espacio modelo","status":"referencia_del_conjunto"}],"geometry":[{"label":"Extensión de la malla en X","value":0.3737339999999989,"unit":"m","source":"Geometría releída del IFC; datum absoluto de proceso provisional","status":"derivado"},{"label":"Extensión de la malla en Y","value":0.20514699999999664,"unit":"m","source":"Geometría releída del IFC; datum absoluto de proceso provisional","status":"derivado"},{"label":"Extensión de la malla en Z","value":2.6,"unit":"m","source":"Geometría releída del IFC; datum absoluto de proceso provisional","status":"derivado"},{"label":"Cota inferior de visualización","value":286.65,"unit":"m","source":"Geometría releída del IFC; datum absoluto de proceso provisional","status":"derivado"},{"label":"Cota superior de visualización","value":289.25,"unit":"m","source":"Geometría releída del IFC; datum absoluto de proceso provisional","status":"derivado"}],"notes":["Las dimensiones del equipo completo se conservan en parentEquipmentDimensions.","Las extensiones en X/Y son de los ejes del modelo y no sustituyen cotas locales de fabricación.","No se infieren espesores de chapa, tolerancias ni dimensiones de piezas a partir de la partición."]} | {"documentId":"EQ-IMPLANTACION-20260430","title":"Plano del fabricante: implantación de equipos","sheet":"LHD2609-GD01000 · espacio modelo","date":"2026-04-30","componentSourceHandles":["71A0C","71A0E","72D2E","72D34","72D35","72D38"]} | {"horizontalStatus":"derivado_del_conjunto","verticalStatus":"derivado_del_conjunto","coordinateSystem":"model_local_m","parentEquipmentId":"AC1001A","transformApplied":false,"note":"Coordenadas copiadas exactamente del equipo coordinado; no se ha movido, girado, elevado ni reescalado este componente.","foundationRelationship":"El apoyo y las cotas de instalación se documentan para el conjunto padre. Esta submalla no acredita un anclaje directo.","meshMinimumAbsoluteElevationM":286.65,"assemblyPlacementField":"parentEquipmentPositioning"} | ["Componente separado de una reconstrucción documental del conjunto. Las alturas y detalles parciales conservan las limitaciones del fabricante registradas en parentEquipmentIssues.","Esta representación exterior no crea una chapa hueca ni añade componentes internos no documentados.","La pertenencia al conjunto no demuestra apoyo o anclaje directo a la cimentación."] | {"source":{"documentId":"EQ-IMPLANTACION-20260430","title":"Plano del fabricante: implantación de equipos","sheet":"LHD2609-GD01000 · espacio modelo","date":"2026-04-30","componentSourceHandles":["71A0C","71A0E","72D2E","72D34","72D35","72D38"]},"sourcePartId":"AC1001A--cad-region-019","sourceHandles":["71A0C","71A0E","72D2E","72D34","72D35","72D38"],"partCount":1,"partsAreBOM":false,"status":"Submalla exacta; interpretación funcional y cotas parciales provisionales."} | {"boundingBoxM":{"min":[49.199679,75.329252,1.65],"max":[49.573413,75.534399,4.25]},"extentsM":[0.373734,0.205147,2.6],"meshSurfaceM2":2.783722,"meshVolumeM3":0.146224,"closedSolid":true,"basis":"Geometría de coordinación. Los volúmenes de referencia y subcomponentes no son cantidades de material ni componentes de fabricación certificados."} | {"documentId":"LHD2609-JG00100-20260904","title":"Cimentaciones y pedestales de equipos · revisión recibida 04/09/2026","date":"2026-09-04","sheet":"1 / 1-1","sourceHandles":["28C35","28C38","28C3B","28C89"]} | equipment | {"id":"equipment","name":"Equipos"} | {"profileId":"equipment_light_gray","name":"Equipo · gris claro provisional","materialName":"No especificado","physicalMaterialStatus":"unknown","physicalMaterialSource":"Sin especificación de material en la documentación revisada","appearanceStatus":"provisional","appearanceBasis":"Referencia visual de fotografías públicas de Jinhong Gas / fabricante. Apariencia provisional para coordinación; fotografías oficiales pueden orientar el color, pero no acreditan el material, el acabado ni el equipo concreto.","appearanceReferences":["jinhong-official-asu"],"note":"El perfil visual no confirma material, grado ni acabado del componente."} | {"status":"componente_independiente","note":"Objeto independiente seleccionable. Las caras se asignan una sola vez entre todos los componentes del conjunto.","parentEquipmentId":"AC1001A","isAssemblyIdentityCarrier":false} | {"elementId":"AC1001A--cad-region-019","ifcGuid":"2ryxANX5jJIutlTmoVEc34","ifcClass":"IfcBuildingElementProxy","buildingId":"process_plant","buildingName":"Planta de proceso","sourceDocumentId":"EQ-IMPLANTACION-20260430","sourceRepresentationKind":"equipmentComponent"} | {"layerId":"equipment","layerName":"Equipos","role":"Componente de equipo · cuerpo o accesorio","basis":"Clasificación por función del elemento; no modifica las especificaciones documentales."} | {"profileId":"equipment_light_gray","name":"Equipo · gris claro provisional","status":"provisional","basis":"Referencia visual de fotografías públicas de Jinhong Gas / fabricante. Apariencia provisional para coordinación; fotografías oficiales pueden orientar el color, pero no acreditan el material, el acabado ni el equipo concreto.","physicalMaterialUnchanged":true} | Equipos | No especificado | Equipos | Equipo · gris claro provisional | provisional | AC1001A--cad-region-019 | ["Componente separado de una reconstrucción documental del conjunto. Las alturas y detalles parciales conservan las limitaciones del fabricante registradas en parentEquipmentIssues.","Esta representación exterior no crea una chapa hueca ni añade componentes internos no documentados.","La pertenencia al conjunto no demuestra apoyo o anclaje directo a la cimentación."] | Geometría de coordinación. Los volúmenes de referencia y subcomponentes no son cantidades de material ni componentes de fabricación certificados. | Sin especificación de material en la documentación revisada | {"documentId":"EQ-IMPLANTACION-20260430","title":"Plano del fabricante: implantación de equipos","sheet":"LHD2609-GD01000 · espacio modelo","date":"2026-04-30","componentSourceHandles":["71A0C","71A0E","72D2E","72D34","72D35","72D38"]} | yes | equipment_light_gray | [0.88,0.89,0.88] | 0.45 | 0.28 | Referencia visual de fotografías públicas de Jinhong Gas / fabricante. Apariencia provisional para coordinación; fotografías oficiales pueden orientar el color, pero no acreditan el material, el acabado ni el equipo concreto. | La apariencia no certifica el material físico ni el acabado de fabricación. | BIM · Equipos | AC1001A | Compresor de aire AC1001A | IfcCompressor | {"documented":[{"label":"Dimensión X local del bastidor de referencia CAD","value":2.35,"unit":"m","source":"EQ-CARGAS-20260825 · contorno CAD · handles 3F3","status":"derivado"},{"label":"Dimensión Y local del bastidor de referencia CAD","value":5.22,"unit":"m","source":"EQ-CARGAS-20260825 · contorno CAD · handles 3F3","status":"derivado"},{"label":"Altura acotada","value":3.38,"unit":"m","source":"EQ-CARGAS-20260825 · handle 52E","status":"documentado"},{"label":"Cota relativa de la superficie de apoyo","value":0.4,"unit":"m","source":"LHD2609-JG00100-20260904 · sección 1 / 1-1 · 28C35, 28C38, 28C3B, 28C89","status":"documentado"}],"geometry":[{"label":"Extensión de la malla en X","value":3.1775829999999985,"unit":"m","source":"Geometría releída del IFC; datum absoluto de proceso provisional","status":"derivado"},{"label":"Extensión de la malla en Y","value":6.404527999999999,"unit":"m","source":"Geometría releída del IFC; datum absoluto de proceso provisional","status":"derivado"},{"label":"Extensión de la malla en Z","value":3.3800000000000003,"unit":"m","source":"Geometría releída del IFC; datum absoluto de proceso provisional","status":"derivado"},{"label":"Cota inferior de visualización","value":286.5,"unit":"m","source":"Geometría releída del IFC; datum absoluto de proceso provisional","status":"derivado"},{"label":"Cota superior de visualización","value":289.88,"unit":"m","source":"Geometría releída del IFC; datum absoluto de proceso provisional","status":"derivado"}],"notes":["Las extensiones de la malla se miden en los ejes del proyecto tras el giro de implantación; no sustituyen las dimensiones locales del fabricante.","La envolvente, su volumen y los espesores de visualización no son volúmenes de material ni cantidades de compra, construcción o fabricación.","Las dimensiones documentadas distinguen cotas explícitas y medidas extraídas de contornos CAD; las dimensiones geométricas describen únicamente la malla publicada.","Las extensiones de la malla refinada y las dimensiones documentadas del contorno o bastidor tienen distinto alcance; las cotas parciales del detalle son provisionales."]} | {"Estado de la planta":"Derivado del CAD y del giro de implantación","Nivel relativo del apoyo (m)":0.4,"Estado del nivel relativo":"Documentado en el plano de cimentaciones","Cero absoluto de visualización (m)":286.1,"Estado del cero absoluto":"Provisional","Cota del apoyo de visualización (m)":286.5,"Desplazamiento aplicado a la malla (m)":0.40000000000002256,"Criterio":"Nivel de apoyo relativo documentado. Se adopta el cero de proceso a 286,10 m solo para visualización; la equivalencia absoluta no está confirmada. No se añade un espesor de montaje sin cota del fabricante."} | ["La máquina está contenida en la envolvente de la cabina acústica; su superposición no acredita una interferencia física.","El bastidor CAD coincide con la referencia de 2,35 × 5,22 m del plano de cargas, pero cuerpos y auxiliares del detalle de abril sobresalen de esa referencia, hasta aproximadamente 1,048 m por el extremo sur y 0,246 m por el lado oeste. Extensión geométrica resultante: 2,595899 × 6,268101 × 3,38 m, derivada y pendiente de coordinación entre revisiones. Permanecen dentro de la cabina acústica. Compatibilidad de revisión pendiente de fabricante.","Todas las alturas parciales son hipótesis de visualización; solo la altura total de 3,38 m está acotada.","Las regiones del dibujo se usan como envolventes de cuerpos; la identificación funcional y la cota Z de cada pieza requieren verificación.","Pequeños taladros, tornillería y detalles interiores de las regiones no se extruyen como vacíos de fabricación.","El bastidor documentado mide 2,35 × 5,22 m. Los accesorios del detalle de abril sobresalen; el conjunto refinado ocupa aproximadamente 2,596 × 6,268 m en ejes del fabricante, pendiente de coordinación entre revisiones.","El acabado de grout HA-35 de 50 mm termina en +0,400; el hormigón termina en +0,350. La losa MAC contigua termina en +0,200.","El cero absoluto de la revisión no está definido; 286,10 m sigue siendo una hipótesis de coordinación.","Se alinea el punto inferior del conjunto del equipo, incluidos los pies ya representados, con la superficie de apoyo terminada; no se añade un espesor de calzos, placa o grout del fabricante no documentado."] | {"revision":"Detalle en planta de 2026-04-30 coordinado de forma preliminar con envolventes y alturas de 2026-08-25","status":"provisional","verticalRule":"Altura total documentada: 3,38 m. Plataforma gráfica de 0,15 m; los cuerpos extraídos de la planta reciben alturas provisionales entre 1,00 y 3,38 m, detalladas por subvolumen. No se dispone de alzado acotado de cada componente.","partCount":26,"source":{"documentId":"EQ-IMPLANTACION-20260430","title":"Plano del fabricante: implantación de equipos","sheet":"LHD2609-GD01000 · espacio modelo","date":"2026-04-30"},"heightSource":{"documentId":"EQ-CARGAS-20260825","title":"Plano del fabricante: cargas de equipos","sheet":"Espacio modelo","date":"2026-08-25"},"unconfirmedDimensions":["Todas las alturas parciales son hipótesis de visualización; solo la altura total de 3,38 m está acotada.","Las regiones del dibujo se usan como envolventes de cuerpos; la identificación funcional y la cota Z de cada pieza requieren verificación.","Pequeños taladros, tornillería y detalles interiores de las regiones no se extruyen como vacíos de fabricación."],"quantityUse":"Magnitudes de la geometría representada; no son cantidades de material, obra, compra, capacidad útil ni fabricación. En geometrías compuestas se suman superficies y volúmenes de partes y pueden existir solapes no depurados.","partsAreBOM":false} | equipment_component | {"min":[48.139687,70.121823,1.5],"max":[51.31727,76.526351,4.88]} | {"boundingBoxM":{"min":[48.139687,70.121823,1.5],"max":[51.31727,76.526351,4.88]},"extentsM":[3.1775829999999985,6.404527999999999,3.38],"meshSurfaceM2":165.1982435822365,"meshVolumeM3":20.17009895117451,"closedSolid":true,"windingConsistent":true,"basis":"Submalla exacta de los triángulos del modelo IFC coordinado; separación de componentes sin transformación ni retesselación."} | ["Todas las alturas parciales son hipótesis de visualización; solo la altura total de 3,38 m está acotada.","Las regiones del dibujo se usan como envolventes de cuerpos; la identificación funcional y la cota Z de cada pieza requieren verificación.","Pequeños taladros, tornillería y detalles interiores de las regiones no se extruyen como vacíos de fabricación.","La separación gráfica no aporta cotas de fabricación ni identifica piezas internas no documentadas.","Los materiales y acabados permanecen provisionales; las fotografías públicas solo orientan la apariencia."] | {"id":"AC1001A--cad-region-019","sourcePartId":"AC1001A--cad-region-019","name":"Cuerpo de equipo · región CAD 19","role":"equipment_component","classificationStatus":"provisional","classificationBasis":"Rol del subvolumen gráfico según el activo de detalle; identidad de fabricación no confirmada.","parentEquipmentId":"AC1001A","parentEquipmentGuid":"1ZhOcwnsbMzxhqtlvKa3pG","isAssemblyIdentityCarrier":false,"sourceFaceRange":[1360,1372],"sourceCurrentFaceIndices":[1360,1361,1362,1363,1364,1365,1366,1367,1368,1369,1370,1371],"sourceMeshSha256":"7b60c904c9d84d22fded9be34af09a09a9c198ec8e75e61902634d5e4064c761","sourceVertexIndices":[714,715,716,717,718,719,720,721],"separationMethod":"Partición exacta de triángulos existentes; coordenadas y orientación de caras conservadas.","quantityUse":"Magnitudes geométricas del subvolumen; no son cantidades netas de material, fabricación, suministro o capacidad."} | {"id":"AC1001A","name":"Compresor de aire AC1001A","relationship":"decomposed_component","parentShapeMeaning":"La forma del objeto que conserva el ID del equipo es únicamente su componente principal; el conjunto completo requiere sus hijos."} | {"kind":"through_parent","parentEquipmentId":"AC1001A","directAnchorageVerified":false,"note":"La relación del conjunto con cimentaciones se conserva en el objeto que mantiene el ID del equipo; no se atribuye fijación directa a cada subcomponente."} | Documento de implantación y apoyo del conjunto padre; no acredita fijación individual de este componente. | AC1001A--cad-region-019 | Cuerpo de equipo · región CAD 19 | Equipos | unknown | equipment_light_gray | {"documentId":"EQ-IMPLANTACION-20260430","title":"Plano del fabricante: implantación de equipos","sheet":"LHD2609-GD01000 · espacio modelo","date":"2026-04-30","componentSourceHandles":["71A0C","71A0E","72D2E","72D34","72D35","72D38"]} | Submalla de triángulos existentes; no hay nueva posición ni nuevas caras. | Cotas globales del conjunto conservadas aparte; las dimensiones de esta ficha son de la submalla. | Coordinación del conjunto padre; anclaje directo individual no acreditado. | Superficie y volumen geométricos brutos; no constituyen cantidades netas de obra, material o fabricación. | Plano general y dimensiones globales de AC1001A; no se asignan esas dimensiones globales a este componente. | ["71A0C","71A0E","72D2E","72D34","72D35","72D38"] | 1 | no | Submalla exacta; interpretación funcional y cotas parciales provisionales.
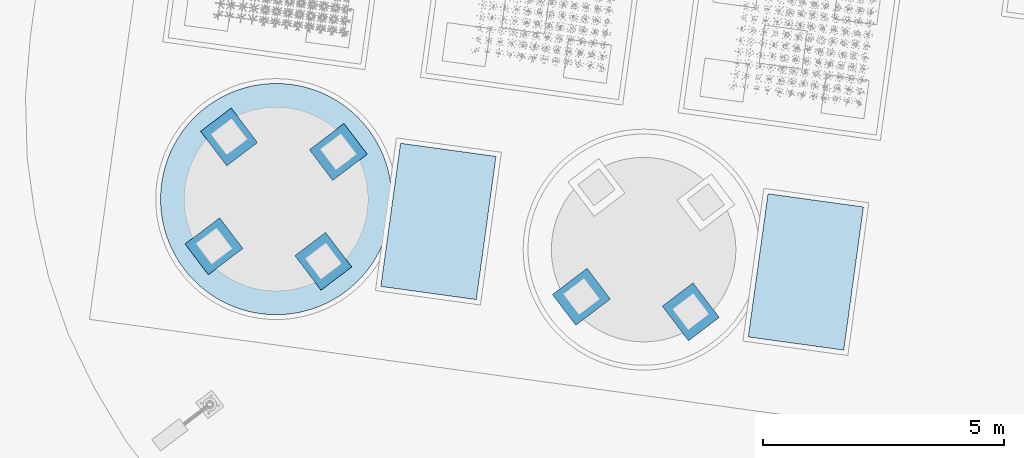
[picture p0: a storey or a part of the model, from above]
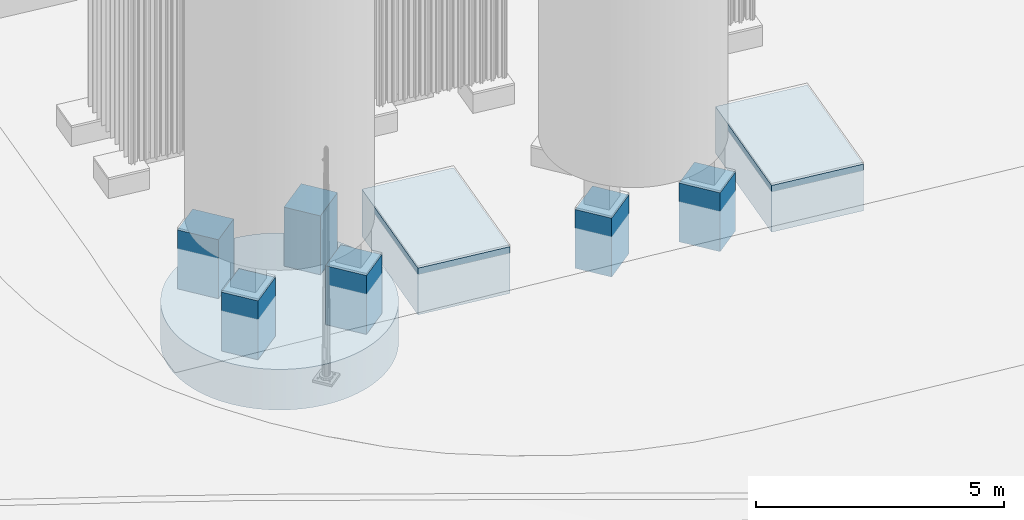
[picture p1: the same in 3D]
Properties of the parts of a building model (IFC4), part 32 of 134

# IfcBuildingElementProxy (140)
Name | Description | Document | Extensión de la malla en X (m) = ExtensionX (m) | Extensión de la malla en Y (m) = ExtensionY (m) | Extensión de la malla en Z (m) = ExtensionZ (m) | Cota inferior de visualización (m) | Cota superior de visualización (m) | SuperficieDeLaMalla (m2) | VolumenGeometrico (m3) | level | category = Categoria = Funcion | representationKind | material | dimensions | JH_InformacionBIM, source = DocumentoFuente | positioning = PosicionYEstado | issues | detailGeometry | geometryMetrics | installationSource | layerId = IdentificadorCapa | visualLayer | materialAppearance | componentSeparation | visualizationIdentity | classification | appearance | Disciplina | Material | Capa BIM = NombreCapa | Acabado de visualización = Acabado | Estado del acabado = Estado | Identificador | JH_Trazabilidad, IncidenciasPendientes | UsoDeLasMagnitudes | JH_EvidenciaDeMaterial, source | JH_DetalleGeometrico, source | VisibilidadInicial | Perfil | ColorRGB | Rugosidad | Metallicidad | Referencia | Nota | Group | parentEquipmentId = Identificador del equipo padre | parentEquipmentName = Equipo padre | parentEquipmentIfcClass | parentEquipmentDimensions | parentEquipmentPositioning | parentEquipmentIssues | parentEquipmentDetail | componentRole = Rol del componente | assemblyBBox | assemblyGeometryMetrics | manufacturerDetailsPending | component | assembly | foundationRelationship | installationSourceScope | Identificador del elemento = sourcePartId | Componente | Capa de visualización | Estado del material | Perfil visual del material | Fuente del componente | Criterio de partición | Criterio de las dimensiones | Relación con cimentaciones | Aplicabilidad de las mediciones | Referencia dimensional del conjunto | sourceHandles | partCount | partsAreBOM | status
Compresor de aire AC1001A · Cuerpo de equipo · región CAD 29 | Componente de equipo · cuerpo o accesorio | Plano del fabricante: implantación de equipos · referencia E7 | 0.510277 | 0.21745 | 2.3 | 286.65 | 288.95 | 3.78959 | 0.078487 | Apoyo relativo +0.400 m; cero absoluto provisional | Componente de equipo · cuerpo o accesorio | equipmentComponent | {"name":"No especificado","source":"Sin especificación de material en la documentación revisada","status":"unknown"} | {"documented":[{"label":"Referencia dimensional del conjunto","value":"Plano general y dimensiones globales de AC1001A; no se asignan esas dimensiones globales a este componente.","unit":"","source":"EQ-IMPLANTACION-20260430 · LHD2609-GD01000 · espacio modelo","status":"referencia_del_conjunto"}],"geometry":[{"label":"Extensión de la malla en X","value":0.510276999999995,"unit":"m","source":"Geometría releída del IFC; datum absoluto de proceso provisional","status":"derivado"},{"label":"Extensión de la malla en Y","value":0.21744999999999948,"unit":"m","source":"Geometría releída del IFC; datum absoluto de proceso provisional","status":"derivado"},{"label":"Extensión de la malla en Z","value":2.3000000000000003,"unit":"m","source":"Geometría releída del IFC; datum absoluto de proceso provisional","status":"derivado"},{"label":"Cota inferior de visualización","value":286.65,"unit":"m","source":"Geometría releída del IFC; datum absoluto de proceso provisional","status":"derivado"},{"label":"Cota superior de visualización","value":288.95,"unit":"m","source":"Geometría releída del IFC; datum absoluto de proceso provisional","status":"derivado"}],"notes":["Las dimensiones del equipo completo se conservan en parentEquipmentDimensions.","Las extensiones en X/Y son de los ejes del modelo y no sustituyen cotas locales de fabricación.","No se infieren espesores de chapa, tolerancias ni dimensiones de piezas a partir de la partición."]} | {"documentId":"EQ-IMPLANTACION-20260430","title":"Plano del fabricante: implantación de equipos","sheet":"LHD2609-GD01000 · espacio modelo","date":"2026-04-30","componentSourceHandles":["717F2","71A09","71A0B","71A11","71A3C","71A3F","71A40","71A41","71A42","71A43","71A5B","71DCB","71E9B","728D5","728E4","728E5","728F2","72D37","72D38","72D3F","72D40","72D41","72D42","72E80","72E81"]} | {"horizontalStatus":"derivado_del_conjunto","verticalStatus":"derivado_del_conjunto","coordinateSystem":"model_local_m","parentEquipmentId":"AC1001A","transformApplied":false,"note":"Coordenadas copiadas exactamente del equipo coordinado; no se ha movido, girado, elevado ni reescalado este componente.","foundationRelationship":"El apoyo y las cotas de instalación se documentan para el conjunto padre. Esta submalla no acredita un anclaje directo.","meshMinimumAbsoluteElevationM":286.65,"assemblyPlacementField":"parentEquipmentPositioning"} | ["Componente separado de una reconstrucción documental del conjunto. Las alturas y detalles parciales conservan las limitaciones del fabricante registradas en parentEquipmentIssues.","Esta representación exterior no crea una chapa hueca ni añade componentes internos no documentados.","La pertenencia al conjunto no demuestra apoyo o anclaje directo a la cimentación."] | {"source":{"documentId":"EQ-IMPLANTACION-20260430","title":"Plano del fabricante: implantación de equipos","sheet":"LHD2609-GD01000 · espacio modelo","date":"2026-04-30","componentSourceHandles":["717F2","71A09","71A0B","71A11","71A3C","71A3F","71A40","71A41","71A42","71A43","71A5B","71DCB","71E9B","728D5","728E4","728E5","728F2","72D37","72D38","72D3F","72D40","72D41","72D42","72E80","72E81"]},"sourcePartId":"AC1001A--cad-region-029","sourceHandles":["717F2","71A09","71A0B","71A11","71A3C","71A3F","71A40","71A41","71A42","71A43","71A5B","71DCB","71E9B","728D5","728E4","728E5","728F2","72D37","72D38","72D3F","72D40","72D41","72D42","72E80","72E81"],"partCount":1,"partsAreBOM":false,"status":"Submalla exacta; interpretación funcional y cotas parciales provisionales."} | {"boundingBoxM":{"min":[49.060608,75.157584,1.65],"max":[49.570885,75.375034,3.95]},"extentsM":[0.510277,0.21745,2.3],"meshSurfaceM2":3.789593,"meshVolumeM3":0.078487,"closedSolid":true,"basis":"Geometría de coordinación. Los volúmenes de referencia y subcomponentes no son cantidades de material ni componentes de fabricación certificados."} | {"documentId":"LHD2609-JG00100-20260904","title":"Cimentaciones y pedestales de equipos · revisión recibida 04/09/2026","date":"2026-09-04","sheet":"1 / 1-1","sourceHandles":["28C35","28C38","28C3B","28C89"]} | equipment | {"id":"equipment","name":"Equipos"} | {"profileId":"equipment_light_gray","name":"Equipo · gris claro provisional","materialName":"No especificado","physicalMaterialStatus":"unknown","physicalMaterialSource":"Sin especificación de material en la documentación revisada","appearanceStatus":"provisional","appearanceBasis":"Referencia visual de fotografías públicas de Jinhong Gas / fabricante. Apariencia provisional para coordinación; fotografías oficiales pueden orientar el color, pero no acreditan el material, el acabado ni el equipo concreto.","appearanceReferences":["jinhong-official-asu"],"note":"El perfil visual no confirma material, grado ni acabado del componente."} | {"status":"componente_independiente","note":"Objeto independiente seleccionable. Las caras se asignan una sola vez entre todos los componentes del conjunto.","parentEquipmentId":"AC1001A","isAssemblyIdentityCarrier":false} | {"elementId":"AC1001A--cad-region-029","ifcGuid":"0N1qGIX8vI0OXQiLHPklUB","ifcClass":"IfcBuildingElementProxy","buildingId":"process_plant","buildingName":"Planta de proceso","sourceDocumentId":"EQ-IMPLANTACION-20260430","sourceRepresentationKind":"equipmentComponent"} | {"layerId":"equipment","layerName":"Equipos","role":"Componente de equipo · cuerpo o accesorio","basis":"Clasificación por función del elemento; no modifica las especificaciones documentales."} | {"profileId":"equipment_light_gray","name":"Equipo · gris claro provisional","status":"provisional","basis":"Referencia visual de fotografías públicas de Jinhong Gas / fabricante. Apariencia provisional para coordinación; fotografías oficiales pueden orientar el color, pero no acreditan el material, el acabado ni el equipo concreto.","physicalMaterialUnchanged":true} | Equipos | No especificado | Equipos | Equipo · gris claro provisional | provisional | AC1001A--cad-region-029 | ["Componente separado de una reconstrucción documental del conjunto. Las alturas y detalles parciales conservan las limitaciones del fabricante registradas en parentEquipmentIssues.","Esta representación exterior no crea una chapa hueca ni añade componentes internos no documentados.","La pertenencia al conjunto no demuestra apoyo o anclaje directo a la cimentación."] | Geometría de coordinación. Los volúmenes de referencia y subcomponentes no son cantidades de material ni componentes de fabricación certificados. | Sin especificación de material en la documentación revisada | {"documentId":"EQ-IMPLANTACION-20260430","title":"Plano del fabricante: implantación de equipos","sheet":"LHD2609-GD01000 · espacio modelo","date":"2026-04-30","componentSourceHandles":["717F2","71A09","71A0B","71A11","71A3C","71A3F","71A40","71A41","71A42","71A43","71A5B","71DCB","71E9B","728D5","728E4","728E5","728F2","72D37","72D38","72D3F","72D40","72D41","72D42","72E80","72E81"]} | yes | equipment_light_gray | [0.88,0.89,0.88] | 0.45 | 0.28 | Referencia visual de fotografías públicas de Jinhong Gas / fabricante. Apariencia provisional para coordinación; fotografías oficiales pueden orientar el color, pero no acreditan el material, el acabado ni el equipo concreto. | La apariencia no certifica el material físico ni el acabado de fabricación. | BIM · Equipos | AC1001A | Compresor de aire AC1001A | IfcCompressor | {"documented":[{"label":"Dimensión X local del bastidor de referencia CAD","value":2.35,"unit":"m","source":"EQ-CARGAS-20260825 · contorno CAD · handles 3F3","status":"derivado"},{"label":"Dimensión Y local del bastidor de referencia CAD","value":5.22,"unit":"m","source":"EQ-CARGAS-20260825 · contorno CAD · handles 3F3","status":"derivado"},{"label":"Altura acotada","value":3.38,"unit":"m","source":"EQ-CARGAS-20260825 · handle 52E","status":"documentado"},{"label":"Cota relativa de la superficie de apoyo","value":0.4,"unit":"m","source":"LHD2609-JG00100-20260904 · sección 1 / 1-1 · 28C35, 28C38, 28C3B, 28C89","status":"documentado"}],"geometry":[{"label":"Extensión de la malla en X","value":3.1775829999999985,"unit":"m","source":"Geometría releída del IFC; datum absoluto de proceso provisional","status":"derivado"},{"label":"Extensión de la malla en Y","value":6.404527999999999,"unit":"m","source":"Geometría releída del IFC; datum absoluto de proceso provisional","status":"derivado"},{"label":"Extensión de la malla en Z","value":3.3800000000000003,"unit":"m","source":"Geometría releída del IFC; datum absoluto de proceso provisional","status":"derivado"},{"label":"Cota inferior de visualización","value":286.5,"unit":"m","source":"Geometría releída del IFC; datum absoluto de proceso provisional","status":"derivado"},{"label":"Cota superior de visualización","value":289.88,"unit":"m","source":"Geometría releída del IFC; datum absoluto de proceso provisional","status":"derivado"}],"notes":["Las extensiones de la malla se miden en los ejes del proyecto tras el giro de implantación; no sustituyen las dimensiones locales del fabricante.","La envolvente, su volumen y los espesores de visualización no son volúmenes de material ni cantidades de compra, construcción o fabricación.","Las dimensiones documentadas distinguen cotas explícitas y medidas extraídas de contornos CAD; las dimensiones geométricas describen únicamente la malla publicada.","Las extensiones de la malla refinada y las dimensiones documentadas del contorno o bastidor tienen distinto alcance; las cotas parciales del detalle son provisionales."]} | {"Estado de la planta":"Derivado del CAD y del giro de implantación","Nivel relativo del apoyo (m)":0.4,"Estado del nivel relativo":"Documentado en el plano de cimentaciones","Cero absoluto de visualización (m)":286.1,"Estado del cero absoluto":"Provisional","Cota del apoyo de visualización (m)":286.5,"Desplazamiento aplicado a la malla (m)":0.40000000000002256,"Criterio":"Nivel de apoyo relativo documentado. Se adopta el cero de proceso a 286,10 m solo para visualización; la equivalencia absoluta no está confirmada. No se añade un espesor de montaje sin cota del fabricante."} | ["La máquina está contenida en la envolvente de la cabina acústica; su superposición no acredita una interferencia física.","El bastidor CAD coincide con la referencia de 2,35 × 5,22 m del plano de cargas, pero cuerpos y auxiliares del detalle de abril sobresalen de esa referencia, hasta aproximadamente 1,048 m por el extremo sur y 0,246 m por el lado oeste. Extensión geométrica resultante: 2,595899 × 6,268101 × 3,38 m, derivada y pendiente de coordinación entre revisiones. Permanecen dentro de la cabina acústica. Compatibilidad de revisión pendiente de fabricante.","Todas las alturas parciales son hipótesis de visualización; solo la altura total de 3,38 m está acotada.","Las regiones del dibujo se usan como envolventes de cuerpos; la identificación funcional y la cota Z de cada pieza requieren verificación.","Pequeños taladros, tornillería y detalles interiores de las regiones no se extruyen como vacíos de fabricación.","El bastidor documentado mide 2,35 × 5,22 m. Los accesorios del detalle de abril sobresalen; el conjunto refinado ocupa aproximadamente 2,596 × 6,268 m en ejes del fabricante, pendiente de coordinación entre revisiones.","El acabado de grout HA-35 de 50 mm termina en +0,400; el hormigón termina en +0,350. La losa MAC contigua termina en +0,200.","El cero absoluto de la revisión no está definido; 286,10 m sigue siendo una hipótesis de coordinación.","Se alinea el punto inferior del conjunto del equipo, incluidos los pies ya representados, con la superficie de apoyo terminada; no se añade un espesor de calzos, placa o grout del fabricante no documentado."] | {"revision":"Detalle en planta de 2026-04-30 coordinado de forma preliminar con envolventes y alturas de 2026-08-25","status":"provisional","verticalRule":"Altura total documentada: 3,38 m. Plataforma gráfica de 0,15 m; los cuerpos extraídos de la planta reciben alturas provisionales entre 1,00 y 3,38 m, detalladas por subvolumen. No se dispone de alzado acotado de cada componente.","partCount":26,"source":{"documentId":"EQ-IMPLANTACION-20260430","title":"Plano del fabricante: implantación de equipos","sheet":"LHD2609-GD01000 · espacio modelo","date":"2026-04-30"},"heightSource":{"documentId":"EQ-CARGAS-20260825","title":"Plano del fabricante: cargas de equipos","sheet":"Espacio modelo","date":"2026-08-25"},"unconfirmedDimensions":["Todas las alturas parciales son hipótesis de visualización; solo la altura total de 3,38 m está acotada.","Las regiones del dibujo se usan como envolventes de cuerpos; la identificación funcional y la cota Z de cada pieza requieren verificación.","Pequeños taladros, tornillería y detalles interiores de las regiones no se extruyen como vacíos de fabricación."],"quantityUse":"Magnitudes de la geometría representada; no son cantidades de material, obra, compra, capacidad útil ni fabricación. En geometrías compuestas se suman superficies y volúmenes de partes y pueden existir solapes no depurados.","partsAreBOM":false} | equipment_component | {"min":[48.139687,70.121823,1.5],"max":[51.31727,76.526351,4.88]} | {"boundingBoxM":{"min":[48.139687,70.121823,1.5],"max":[51.31727,76.526351,4.88]},"extentsM":[3.1775829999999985,6.404527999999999,3.38],"meshSurfaceM2":165.1982435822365,"meshVolumeM3":20.17009895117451,"closedSolid":true,"windingConsistent":true,"basis":"Submalla exacta de los triángulos del modelo IFC coordinado; separación de componentes sin transformación ni retesselación."} | ["Todas las alturas parciales son hipótesis de visualización; solo la altura total de 3,38 m está acotada.","Las regiones del dibujo se usan como envolventes de cuerpos; la identificación funcional y la cota Z de cada pieza requieren verificación.","Pequeños taladros, tornillería y detalles interiores de las regiones no se extruyen como vacíos de fabricación.","La separación gráfica no aporta cotas de fabricación ni identifica piezas internas no documentadas.","Los materiales y acabados permanecen provisionales; las fotografías públicas solo orientan la apariencia."] | {"id":"AC1001A--cad-region-029","sourcePartId":"AC1001A--cad-region-029","name":"Cuerpo de equipo · región CAD 29","role":"equipment_component","classificationStatus":"provisional","classificationBasis":"Rol del subvolumen gráfico según el activo de detalle; identidad de fabricación no confirmada.","parentEquipmentId":"AC1001A","parentEquipmentGuid":"1ZhOcwnsbMzxhqtlvKa3pG","isAssemblyIdentityCarrier":false,"sourceFaceRange":[2268,2432],"sourceCurrentFaceIndices":[2268,2269,2270,2271,2272,2273,2274,2275,2276,2277,2278,2279,2280,2281,2282,2283,2284,2285,2286,2287,2288,2289,2290,2291,2292,2293,2294,2295,2296,2297,2298,2299,2300,2301,2302,2303,2304,2305,2306,2307,2308,2309,2310,2311,2312,2313,2314,2315,2316,2317,2318,2319,2320,2321,2322,2323,2324,2325,2326,2327,2328,2329,2330,2331,2332,2333,2334,2335,2336,2337,2338,2339,2340,2341,2342,2343,2344,2345,2346,2347,2348,2349,2350,2351,2352,2353,2354,2355,2356,2357,2358,2359,2360,2361,2362,2363,2364,2365,2366,2367,2368,2369,2370,2371,2372,2373,2374,2375,2376,2377,2378,2379,2380,2381,2382,2383,2384,2385,2386,2387,2388,2389,2390,2391,2392,2393,2394,2395,2396,2397,2398,2399,2400,2401,2402,2403,2404,2405,2406,2407,2408,2409,2410,2411,2412,2413,2414,2415,2416,2417,2418,2419,2420,2421,2422,2423,2424,2425,2426,2427,2428,2429,2430,2431],"sourceMeshSha256":"7b60c904c9d84d22fded9be34af09a09a9c198ec8e75e61902634d5e4064c761","sourceVertexIndices":[1182,1183,1184,1185,1186,1187,1188,1189,1190,1191,1192,1193,1194,1195,1196,1197,1198,1199,1200,1201,1202,1203,1204,1205,1206,1207,1208,1209,1210,1211,1212,1213,1214,1215,1216,1217,1218,1219,1220,1221,1222,1223,1224,1225,1226,1227,1228,1229,1230,1231,1232,1233,1234,1235,1236,1237,1238,1239,1240,1241,1242,1243,1244,1245,1246,1247,1248,1249,1250,1251,1252,1253,1254,1255,1256,1257,1258,1259,1260,1261,1262,1263,1264,1265],"separationMethod":"Partición exacta de triángulos existentes; coordenadas y orientación de caras conservadas.","quantityUse":"Magnitudes geométricas del subvolumen; no son cantidades netas de material, fabricación, suministro o capacidad."} | {"id":"AC1001A","name":"Compresor de aire AC1001A","relationship":"decomposed_component","parentShapeMeaning":"La forma del objeto que conserva el ID del equipo es únicamente su componente principal; el conjunto completo requiere sus hijos."} | {"kind":"through_parent","parentEquipmentId":"AC1001A","directAnchorageVerified":false,"note":"La relación del conjunto con cimentaciones se conserva en el objeto que mantiene el ID del equipo; no se atribuye fijación directa a cada subcomponente."} | Documento de implantación y apoyo del conjunto padre; no acredita fijación individual de este componente. | AC1001A--cad-region-029 | Cuerpo de equipo · región CAD 29 | Equipos | unknown | equipment_light_gray | {"documentId":"EQ-IMPLANTACION-20260430","title":"Plano del fabricante: implantación de equipos","sheet":"LHD2609-GD01000 · espacio modelo","date":"2026-04-30","componentSourceHandles":["717F2","71A09","71A0B","71A11","71A3C","71A3F","71A40","71A41","71A42","71A43","71A5B","71DCB","71E9B","728D5","728E4","728E5","728F2","72D37","72D38","72D3F","72D40","72D41","72D42","72E80","72E81"]} | Submalla de triángulos existentes; no hay nueva posición ni nuevas caras. | Cotas globales del conjunto conservadas aparte; las dimensiones de esta ficha son de la submalla. | Coordinación del conjunto padre; anclaje directo individual no acreditado. | Superficie y volumen geométricos brutos; no constituyen cantidades netas de obra, material o fabricación. | Plano general y dimensiones globales de AC1001A; no se asignan esas dimensiones globales a este componente. | ["717F2","71A09","71A0B","71A11","71A3C","71A3F","71A40","71A41","71A42","71A43","71A5B","71DCB","71E9B","728D5","728E4","728E5","728F2","72D37","72D38","72D3F","72D40","72D41","72D42","72E80","72E81"] | 1 | no | Submalla exacta; interpretación funcional y cotas parciales provisionales.
Compresor de aire AC1001A · Cuerpo de equipo · región CAD 35 | Componente de equipo · cuerpo o accesorio | Plano del fabricante: implantación de equipos · referencia E7 | 0.353966 | 0.134878 | 2.35 | 286.65 | 289 | 2.10008 | 0.071935 | Apoyo relativo +0.400 m; cero absoluto provisional | Componente de equipo · cuerpo o accesorio | equipmentComponent | {"name":"No especificado","source":"Sin especificación de material en la documentación revisada","status":"unknown"} | {"documented":[{"label":"Referencia dimensional del conjunto","value":"Plano general y dimensiones globales de AC1001A; no se asignan esas dimensiones globales a este componente.","unit":"","source":"EQ-IMPLANTACION-20260430 · LHD2609-GD01000 · espacio modelo","status":"referencia_del_conjunto"}],"geometry":[{"label":"Extensión de la malla en X","value":0.3539660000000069,"unit":"m","source":"Geometría releída del IFC; datum absoluto de proceso provisional","status":"derivado"},{"label":"Extensión de la malla en Y","value":0.1348780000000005,"unit":"m","source":"Geometría releída del IFC; datum absoluto de proceso provisional","status":"derivado"},{"label":"Extensión de la malla en Z","value":2.35,"unit":"m","source":"Geometría releída del IFC; datum absoluto de proceso provisional","status":"derivado"},{"label":"Cota inferior de visualización","value":286.65,"unit":"m","source":"Geometría releída del IFC; datum absoluto de proceso provisional","status":"derivado"},{"label":"Cota superior de visualización","value":289.0,"unit":"m","source":"Geometría releída del IFC; datum absoluto de proceso provisional","status":"derivado"}],"notes":["Las dimensiones del equipo completo se conservan en parentEquipmentDimensions.","Las extensiones en X/Y son de los ejes del modelo y no sustituyen cotas locales de fabricación.","No se infieren espesores de chapa, tolerancias ni dimensiones de piezas a partir de la partición."]} | {"documentId":"EQ-IMPLANTACION-20260430","title":"Plano del fabricante: implantación de equipos","sheet":"LHD2609-GD01000 · espacio modelo","date":"2026-04-30","componentSourceHandles":["7134F","719FC","719FD","719FE","71A18","71A1A","71A45","71A46","71A4D","71A58","71A59","71DB1","72F11"]} | {"horizontalStatus":"derivado_del_conjunto","verticalStatus":"derivado_del_conjunto","coordinateSystem":"model_local_m","parentEquipmentId":"AC1001A","transformApplied":false,"note":"Coordenadas copiadas exactamente del equipo coordinado; no se ha movido, girado, elevado ni reescalado este componente.","foundationRelationship":"El apoyo y las cotas de instalación se documentan para el conjunto padre. Esta submalla no acredita un anclaje directo.","meshMinimumAbsoluteElevationM":286.65,"assemblyPlacementField":"parentEquipmentPositioning"} | ["Componente separado de una reconstrucción documental del conjunto. Las alturas y detalles parciales conservan las limitaciones del fabricante registradas en parentEquipmentIssues.","Esta representación exterior no crea una chapa hueca ni añade componentes internos no documentados.","La pertenencia al conjunto no demuestra apoyo o anclaje directo a la cimentación."] | {"source":{"documentId":"EQ-IMPLANTACION-20260430","title":"Plano del fabricante: implantación de equipos","sheet":"LHD2609-GD01000 · espacio modelo","date":"2026-04-30","componentSourceHandles":["7134F","719FC","719FD","719FE","71A18","71A1A","71A45","71A46","71A4D","71A58","71A59","71DB1","72F11"]},"sourcePartId":"AC1001A--cad-region-035","sourceHandles":["7134F","719FC","719FD","719FE","71A18","71A1A","71A45","71A46","71A4D","71A58","71A59","71DB1","72F11"],"partCount":1,"partsAreBOM":false,"status":"Submalla exacta; interpretación funcional y cotas parciales provisionales."} | {"boundingBoxM":{"min":[50.295852,75.174712,1.65],"max":[50.649818,75.30959,4.0]},"extentsM":[0.353966,0.134878,2.35],"meshSurfaceM2":2.100085,"meshVolumeM3":0.071935,"closedSolid":true,"basis":"Geometría de coordinación. Los volúmenes de referencia y subcomponentes no son cantidades de material ni componentes de fabricación certificados."} | {"documentId":"LHD2609-JG00100-20260904","title":"Cimentaciones y pedestales de equipos · revisión recibida 04/09/2026","date":"2026-09-04","sheet":"1 / 1-1","sourceHandles":["28C35","28C38","28C3B","28C89"]} | equipment | {"id":"equipment","name":"Equipos"} | {"profileId":"equipment_light_gray","name":"Equipo · gris claro provisional","materialName":"No especificado","physicalMaterialStatus":"unknown","physicalMaterialSource":"Sin especificación de material en la documentación revisada","appearanceStatus":"provisional","appearanceBasis":"Referencia visual de fotografías públicas de Jinhong Gas / fabricante. Apariencia provisional para coordinación; fotografías oficiales pueden orientar el color, pero no acreditan el material, el acabado ni el equipo concreto.","appearanceReferences":["jinhong-official-asu"],"note":"El perfil visual no confirma material, grado ni acabado del componente."} | {"status":"componente_independiente","note":"Objeto independiente seleccionable. Las caras se asignan una sola vez entre todos los componentes del conjunto.","parentEquipmentId":"AC1001A","isAssemblyIdentityCarrier":false} | {"elementId":"AC1001A--cad-region-035","ifcGuid":"024XNbNVnLyf1s0AS9c7xi","ifcClass":"IfcBuildingElementProxy","buildingId":"process_plant","buildingName":"Planta de proceso","sourceDocumentId":"EQ-IMPLANTACION-20260430","sourceRepresentationKind":"equipmentComponent"} | {"layerId":"equipment","layerName":"Equipos","role":"Componente de equipo · cuerpo o accesorio","basis":"Clasificación por función del elemento; no modifica las especificaciones documentales."} | {"profileId":"equipment_light_gray","name":"Equipo · gris claro provisional","status":"provisional","basis":"Referencia visual de fotografías públicas de Jinhong Gas / fabricante. Apariencia provisional para coordinación; fotografías oficiales pueden orientar el color, pero no acreditan el material, el acabado ni el equipo concreto.","physicalMaterialUnchanged":true} | Equipos | No especificado | Equipos | Equipo · gris claro provisional | provisional | AC1001A--cad-region-035 | ["Componente separado de una reconstrucción documental del conjunto. Las alturas y detalles parciales conservan las limitaciones del fabricante registradas en parentEquipmentIssues.","Esta representación exterior no crea una chapa hueca ni añade componentes internos no documentados.","La pertenencia al conjunto no demuestra apoyo o anclaje directo a la cimentación."] | Geometría de coordinación. Los volúmenes de referencia y subcomponentes no son cantidades de material ni componentes de fabricación certificados. | Sin especificación de material en la documentación revisada | {"documentId":"EQ-IMPLANTACION-20260430","title":"Plano del fabricante: implantación de equipos","sheet":"LHD2609-GD01000 · espacio modelo","date":"2026-04-30","componentSourceHandles":["7134F","719FC","719FD","719FE","71A18","71A1A","71A45","71A46","71A4D","71A58","71A59","71DB1","72F11"]} | yes | equipment_light_gray | [0.88,0.89,0.88] | 0.45 | 0.28 | Referencia visual de fotografías públicas de Jinhong Gas / fabricante. Apariencia provisional para coordinación; fotografías oficiales pueden orientar el color, pero no acreditan el material, el acabado ni el equipo concreto. | La apariencia no certifica el material físico ni el acabado de fabricación. | BIM · Equipos | AC1001A | Compresor de aire AC1001A | IfcCompressor | {"documented":[{"label":"Dimensión X local del bastidor de referencia CAD","value":2.35,"unit":"m","source":"EQ-CARGAS-20260825 · contorno CAD · handles 3F3","status":"derivado"},{"label":"Dimensión Y local del bastidor de referencia CAD","value":5.22,"unit":"m","source":"EQ-CARGAS-20260825 · contorno CAD · handles 3F3","status":"derivado"},{"label":"Altura acotada","value":3.38,"unit":"m","source":"EQ-CARGAS-20260825 · handle 52E","status":"documentado"},{"label":"Cota relativa de la superficie de apoyo","value":0.4,"unit":"m","source":"LHD2609-JG00100-20260904 · sección 1 / 1-1 · 28C35, 28C38, 28C3B, 28C89","status":"documentado"}],"geometry":[{"label":"Extensión de la malla en X","value":3.1775829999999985,"unit":"m","source":"Geometría releída del IFC; datum absoluto de proceso provisional","status":"derivado"},{"label":"Extensión de la malla en Y","value":6.404527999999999,"unit":"m","source":"Geometría releída del IFC; datum absoluto de proceso provisional","status":"derivado"},{"label":"Extensión de la malla en Z","value":3.3800000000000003,"unit":"m","source":"Geometría releída del IFC; datum absoluto de proceso provisional","status":"derivado"},{"label":"Cota inferior de visualización","value":286.5,"unit":"m","source":"Geometría releída del IFC; datum absoluto de proceso provisional","status":"derivado"},{"label":"Cota superior de visualización","value":289.88,"unit":"m","source":"Geometría releída del IFC; datum absoluto de proceso provisional","status":"derivado"}],"notes":["Las extensiones de la malla se miden en los ejes del proyecto tras el giro de implantación; no sustituyen las dimensiones locales del fabricante.","La envolvente, su volumen y los espesores de visualización no son volúmenes de material ni cantidades de compra, construcción o fabricación.","Las dimensiones documentadas distinguen cotas explícitas y medidas extraídas de contornos CAD; las dimensiones geométricas describen únicamente la malla publicada.","Las extensiones de la malla refinada y las dimensiones documentadas del contorno o bastidor tienen distinto alcance; las cotas parciales del detalle son provisionales."]} | {"Estado de la planta":"Derivado del CAD y del giro de implantación","Nivel relativo del apoyo (m)":0.4,"Estado del nivel relativo":"Documentado en el plano de cimentaciones","Cero absoluto de visualización (m)":286.1,"Estado del cero absoluto":"Provisional","Cota del apoyo de visualización (m)":286.5,"Desplazamiento aplicado a la malla (m)":0.40000000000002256,"Criterio":"Nivel de apoyo relativo documentado. Se adopta el cero de proceso a 286,10 m solo para visualización; la equivalencia absoluta no está confirmada. No se añade un espesor de montaje sin cota del fabricante."} | ["La máquina está contenida en la envolvente de la cabina acústica; su superposición no acredita una interferencia física.","El bastidor CAD coincide con la referencia de 2,35 × 5,22 m del plano de cargas, pero cuerpos y auxiliares del detalle de abril sobresalen de esa referencia, hasta aproximadamente 1,048 m por el extremo sur y 0,246 m por el lado oeste. Extensión geométrica resultante: 2,595899 × 6,268101 × 3,38 m, derivada y pendiente de coordinación entre revisiones. Permanecen dentro de la cabina acústica. Compatibilidad de revisión pendiente de fabricante.","Todas las alturas parciales son hipótesis de visualización; solo la altura total de 3,38 m está acotada.","Las regiones del dibujo se usan como envolventes de cuerpos; la identificación funcional y la cota Z de cada pieza requieren verificación.","Pequeños taladros, tornillería y detalles interiores de las regiones no se extruyen como vacíos de fabricación.","El bastidor documentado mide 2,35 × 5,22 m. Los accesorios del detalle de abril sobresalen; el conjunto refinado ocupa aproximadamente 2,596 × 6,268 m en ejes del fabricante, pendiente de coordinación entre revisiones.","El acabado de grout HA-35 de 50 mm termina en +0,400; el hormigón termina en +0,350. La losa MAC contigua termina en +0,200.","El cero absoluto de la revisión no está definido; 286,10 m sigue siendo una hipótesis de coordinación.","Se alinea el punto inferior del conjunto del equipo, incluidos los pies ya representados, con la superficie de apoyo terminada; no se añade un espesor de calzos, placa o grout del fabricante no documentado."] | {"revision":"Detalle en planta de 2026-04-30 coordinado de forma preliminar con envolventes y alturas de 2026-08-25","status":"provisional","verticalRule":"Altura total documentada: 3,38 m. Plataforma gráfica de 0,15 m; los cuerpos extraídos de la planta reciben alturas provisionales entre 1,00 y 3,38 m, detalladas por subvolumen. No se dispone de alzado acotado de cada componente.","partCount":26,"source":{"documentId":"EQ-IMPLANTACION-20260430","title":"Plano del fabricante: implantación de equipos","sheet":"LHD2609-GD01000 · espacio modelo","date":"2026-04-30"},"heightSource":{"documentId":"EQ-CARGAS-20260825","title":"Plano del fabricante: cargas de equipos","sheet":"Espacio modelo","date":"2026-08-25"},"unconfirmedDimensions":["Todas las alturas parciales son hipótesis de visualización; solo la altura total de 3,38 m está acotada.","Las regiones del dibujo se usan como envolventes de cuerpos; la identificación funcional y la cota Z de cada pieza requieren verificación.","Pequeños taladros, tornillería y detalles interiores de las regiones no se extruyen como vacíos de fabricación."],"quantityUse":"Magnitudes de la geometría representada; no son cantidades de material, obra, compra, capacidad útil ni fabricación. En geometrías compuestas se suman superficies y volúmenes de partes y pueden existir solapes no depurados.","partsAreBOM":false} | equipment_component | {"min":[48.139687,70.121823,1.5],"max":[51.31727,76.526351,4.88]} | {"boundingBoxM":{"min":[48.139687,70.121823,1.5],"max":[51.31727,76.526351,4.88]},"extentsM":[3.1775829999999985,6.404527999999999,3.38],"meshSurfaceM2":165.1982435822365,"meshVolumeM3":20.17009895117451,"closedSolid":true,"windingConsistent":true,"basis":"Submalla exacta de los triángulos del modelo IFC coordinado; separación de componentes sin transformación ni retesselación."} | ["Todas las alturas parciales son hipótesis de visualización; solo la altura total de 3,38 m está acotada.","Las regiones del dibujo se usan como envolventes de cuerpos; la identificación funcional y la cota Z de cada pieza requieren verificación.","Pequeños taladros, tornillería y detalles interiores de las regiones no se extruyen como vacíos de fabricación.","La separación gráfica no aporta cotas de fabricación ni identifica piezas internas no documentadas.","Los materiales y acabados permanecen provisionales; las fotografías públicas solo orientan la apariencia."] | {"id":"AC1001A--cad-region-035","sourcePartId":"AC1001A--cad-region-035","name":"Cuerpo de equipo · región CAD 35","role":"equipment_component","classificationStatus":"provisional","classificationBasis":"Rol del subvolumen gráfico según el activo de detalle; identidad de fabricación no confirmada.","parentEquipmentId":"AC1001A","parentEquipmentGuid":"1ZhOcwnsbMzxhqtlvKa3pG","isAssemblyIdentityCarrier":false,"sourceFaceRange":[2432,2444],"sourceCurrentFaceIndices":[2432,2433,2434,2435,2436,2437,2438,2439,2440,2441,2442,2443],"sourceMeshSha256":"7b60c904c9d84d22fded9be34af09a09a9c198ec8e75e61902634d5e4064c761","sourceVertexIndices":[1266,1267,1268,1269,1270,1271,1272,1273],"separationMethod":"Partición exacta de triángulos existentes; coordenadas y orientación de caras conservadas.","quantityUse":"Magnitudes geométricas del subvolumen; no son cantidades netas de material, fabricación, suministro o capacidad."} | {"id":"AC1001A","name":"Compresor de aire AC1001A","relationship":"decomposed_component","parentShapeMeaning":"La forma del objeto que conserva el ID del equipo es únicamente su componente principal; el conjunto completo requiere sus hijos."} | {"kind":"through_parent","parentEquipmentId":"AC1001A","directAnchorageVerified":false,"note":"La relación del conjunto con cimentaciones se conserva en el objeto que mantiene el ID del equipo; no se atribuye fijación directa a cada subcomponente."} | Documento de implantación y apoyo del conjunto padre; no acredita fijación individual de este componente. | AC1001A--cad-region-035 | Cuerpo de equipo · región CAD 35 | Equipos | unknown | equipment_light_gray | {"documentId":"EQ-IMPLANTACION-20260430","title":"Plano del fabricante: implantación de equipos","sheet":"LHD2609-GD01000 · espacio modelo","date":"2026-04-30","componentSourceHandles":["7134F","719FC","719FD","719FE","71A18","71A1A","71A45","71A46","71A4D","71A58","71A59","71DB1","72F11"]} | Submalla de triángulos existentes; no hay nueva posición ni nuevas caras. | Cotas globales del conjunto conservadas aparte; las dimensiones de esta ficha son de la submalla. | Coordinación del conjunto padre; anclaje directo individual no acreditado. | Superficie y volumen geométricos brutos; no constituyen cantidades netas de obra, material o fabricación. | Plano general y dimensiones globales de AC1001A; no se asignan esas dimensiones globales a este componente. | ["7134F","719FC","719FD","719FE","71A18","71A1A","71A45","71A46","71A4D","71A58","71A59","71DB1","72F11"] | 1 | no | Submalla exacta; interpretación funcional y cotas parciales provisionales.
Compresor de aire AC1001B · Envolvente del bastidor de referencia | Componente de equipo · cuerpo o accesorio | Plano del fabricante: cargas de equipos | 3.03909 | 5.49143 | 0.15 | 286.5 | 286.65 | 26.805 | 1.84005 | Apoyo relativo +0.400 m; cero absoluto provisional | Componente de equipo · cuerpo o accesorio | equipmentComponent | {"name":"No especificado","source":"Sin especificación de material en la documentación revisada","status":"unknown"} | {"documented":[{"label":"Referencia dimensional del conjunto","value":"Plano general y dimensiones globales de AC1001B; no se asignan esas dimensiones globales a este componente.","unit":"","source":"EQ-CARGAS-20260825 · Espacio modelo","status":"referencia_del_conjunto"}],"geometry":[{"label":"Extensión de la malla en X","value":3.039085,"unit":"m","source":"Geometría releída del IFC; datum absoluto de proceso provisional","status":"derivado"},{"label":"Extensión de la malla en Y","value":5.491433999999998,"unit":"m","source":"Geometría releída del IFC; datum absoluto de proceso provisional","status":"derivado"},{"label":"Extensión de la malla en Z","value":0.1499999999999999,"unit":"m","source":"Geometría releída del IFC; datum absoluto de proceso provisional","status":"derivado"},{"label":"Cota inferior de visualización","value":286.5,"unit":"m","source":"Geometría releída del IFC; datum absoluto de proceso provisional","status":"derivado"},{"label":"Cota superior de visualización","value":286.65,"unit":"m","source":"Geometría releída del IFC; datum absoluto de proceso provisional","status":"derivado"}],"notes":["Las dimensiones del equipo completo se conservan en parentEquipmentDimensions.","Las extensiones en X/Y son de los ejes del modelo y no sustituyen cotas locales de fabricación.","No se infieren espesores de chapa, tolerancias ni dimensiones de piezas a partir de la partición."]} | {"documentId":"EQ-CARGAS-20260825","title":"Plano del fabricante: cargas de equipos","sheet":"Espacio modelo","date":"2026-08-25","componentSourceHandles":["3ED"]} | {"horizontalStatus":"derivado_del_conjunto","verticalStatus":"derivado_del_conjunto","coordinateSystem":"model_local_m","parentEquipmentId":"AC1001B","transformApplied":false,"note":"Coordenadas copiadas exactamente del equipo coordinado; no se ha movido, girado, elevado ni reescalado este componente.","foundationRelationship":"El apoyo y las cotas de instalación se documentan para el conjunto padre. Esta submalla no acredita un anclaje directo.","meshMinimumAbsoluteElevationM":286.5,"assemblyPlacementField":"parentEquipmentPositioning"} | ["Componente separado de una reconstrucción documental del conjunto. Las alturas y detalles parciales conservan las limitaciones del fabricante registradas en parentEquipmentIssues.","Esta representación exterior no crea una chapa hueca ni añade componentes internos no documentados.","La pertenencia al conjunto no demuestra apoyo o anclaje directo a la cimentación."] | {"source":{"documentId":"EQ-CARGAS-20260825","title":"Plano del fabricante: cargas de equipos","sheet":"Espacio modelo","date":"2026-08-25","componentSourceHandles":["3ED"]},"sourcePartId":"AC1001B--base","sourceHandles":["3ED"],"partCount":1,"partsAreBOM":false,"status":"Submalla exacta; interpretación funcional y cotas parciales provisionales."} | {"boundingBoxM":{"min":[54.618543,70.163212,1.5],"max":[57.657628,75.654646,1.65]},"extentsM":[3.039085,5.491434,0.15],"meshSurfaceM2":26.805003,"meshVolumeM3":1.84005,"closedSolid":true,"basis":"Geometría de coordinación. Los volúmenes de referencia y subcomponentes no son cantidades de material ni componentes de fabricación certificados."} | {"documentId":"LHD2609-JG00100-20260904","title":"Cimentaciones y pedestales de equipos · revisión recibida 04/09/2026","date":"2026-09-04","sheet":"1 / 1-1","sourceHandles":["28C35","28C38","28C3B","28C89"]} | equipment | {"id":"equipment","name":"Equipos"} | {"profileId":"equipment_dark_frame","name":"Bastidor metálico · gris oscuro provisional","materialName":"No especificado","physicalMaterialStatus":"unknown","physicalMaterialSource":"Sin especificación de material en la documentación revisada","appearanceStatus":"provisional","appearanceBasis":"Referencia visual de fotografías públicas de Jinhong Gas / fabricante. Apariencia provisional para coordinación; fotografías oficiales pueden orientar el color, pero no acreditan el material, el acabado ni el equipo concreto.","appearanceReferences":["jinhong-official-asu"],"note":"El perfil visual no confirma material, grado ni acabado del componente."} | {"status":"componente_independiente","note":"Objeto independiente seleccionable. Las caras se asignan una sola vez entre todos los componentes del conjunto.","parentEquipmentId":"AC1001B","isAssemblyIdentityCarrier":false} | {"elementId":"AC1001B--base","ifcGuid":"2PMzYk5jDJ4Rf6qMHmPWwU","ifcClass":"IfcBuildingElementProxy","buildingId":"process_plant","buildingName":"Planta de proceso","sourceDocumentId":"EQ-CARGAS-20260825","sourceRepresentationKind":"equipmentComponent"} | {"layerId":"equipment","layerName":"Equipos","role":"Componente de equipo · cuerpo o accesorio","basis":"Clasificación por función del elemento; no modifica las especificaciones documentales."} | {"profileId":"equipment_dark_frame","name":"Bastidor metálico · gris oscuro provisional","status":"provisional","basis":"Referencia visual de fotografías públicas de Jinhong Gas / fabricante. Apariencia provisional para coordinación; fotografías oficiales pueden orientar el color, pero no acreditan el material, el acabado ni el equipo concreto.","physicalMaterialUnchanged":true} | Equipos | No especificado | Equipos | Bastidor metálico · gris oscuro provisional | provisional | AC1001B--base | ["Componente separado de una reconstrucción documental del conjunto. Las alturas y detalles parciales conservan las limitaciones del fabricante registradas en parentEquipmentIssues.","Esta representación exterior no crea una chapa hueca ni añade componentes internos no documentados.","La pertenencia al conjunto no demuestra apoyo o anclaje directo a la cimentación."] | Geometría de coordinación. Los volúmenes de referencia y subcomponentes no son cantidades de material ni componentes de fabricación certificados. | Sin especificación de material en la documentación revisada | {"documentId":"EQ-CARGAS-20260825","title":"Plano del fabricante: cargas de equipos","sheet":"Espacio modelo","date":"2026-08-25","componentSourceHandles":["3ED"]} | yes | equipment_dark_frame | [0.290196,0.329412,0.34902] | 0.62 | 0.5 | Referencia visual de fotografías públicas de Jinhong Gas / fabricante. Apariencia provisional para coordinación; fotografías oficiales pueden orientar el color, pero no acreditan el material, el acabado ni el equipo concreto. | La apariencia no certifica el material físico ni el acabado de fabricación. | BIM · Equipos | AC1001B | Compresor de aire AC1001B | IfcCompressor | {"documented":[{"label":"Dimensión X local del bastidor de referencia CAD","value":2.35,"unit":"m","source":"EQ-CARGAS-20260825 · contorno CAD · handles 3ED","status":"derivado"},{"label":"Dimensión Y local del bastidor de referencia CAD","value":5.22,"unit":"m","source":"EQ-CARGAS-20260825 · contorno CAD · handles 3ED","status":"derivado"},{"label":"Altura acotada","value":3.38,"unit":"m","source":"EQ-CARGAS-20260825 · handle 25A3","status":"documentado"},{"label":"Cota relativa de la superficie de apoyo","value":0.4,"unit":"m","source":"LHD2609-JG00100-20260904 · sección 1 / 1-1 · 28C35, 28C38, 28C3B, 28C89","status":"documentado"}],"geometry":[{"label":"Extensión de la malla en X","value":3.177584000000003,"unit":"m","source":"Geometría releída del IFC; datum absoluto de proceso provisional","status":"derivado"},{"label":"Extensión de la malla en Y","value":6.404527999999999,"unit":"m","source":"Geometría releída del IFC; datum absoluto de proceso provisional","status":"derivado"},{"label":"Extensión de la malla en Z","value":3.3800000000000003,"unit":"m","source":"Geometría releída del IFC; datum absoluto de proceso provisional","status":"derivado"},{"label":"Cota inferior de visualización","value":286.5,"unit":"m","source":"Geometría releída del IFC; datum absoluto de proceso provisional","status":"derivado"},{"label":"Cota superior de visualización","value":289.88,"unit":"m","source":"Geometría releída del IFC; datum absoluto de proceso provisional","status":"derivado"}],"notes":["Las extensiones de la malla se miden en los ejes del proyecto tras el giro de implantación; no sustituyen las dimensiones locales del fabricante.","La envolvente, su volumen y los espesores de visualización no son volúmenes de material ni cantidades de compra, construcción o fabricación.","Las dimensiones documentadas distinguen cotas explícitas y medidas extraídas de contornos CAD; las dimensiones geométricas describen únicamente la malla publicada.","Las extensiones de la malla refinada y las dimensiones documentadas del contorno o bastidor tienen distinto alcance; las cotas parciales del detalle son provisionales."]} | {"Estado de la planta":"Derivado del CAD y del giro de implantación","Nivel relativo del apoyo (m)":0.4,"Estado del nivel relativo":"Documentado en el plano de cimentaciones","Cero absoluto de visualización (m)":286.1,"Estado del cero absoluto":"Provisional","Cota del apoyo de visualización (m)":286.5,"Desplazamiento aplicado a la malla (m)":0.40000000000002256,"Criterio":"Nivel de apoyo relativo documentado. Se adopta el cero de proceso a 286,10 m solo para visualización; la equivalencia absoluta no está confirmada. No se añade un espesor de montaje sin cota del fabricante."} | ["La máquina está contenida en la envolvente de la cabina acústica; su superposición no acredita una interferencia física.","El bastidor CAD coincide con la referencia de 2,35 × 5,22 m del plano de cargas, pero cuerpos y auxiliares del detalle de abril sobresalen de esa referencia, hasta aproximadamente 1,048 m por el extremo sur y 0,246 m por el lado oeste. Extensión geométrica resultante: 2,595899 × 6,268101 × 3,38 m, derivada y pendiente de coordinación entre revisiones. Permanecen dentro de la cabina acústica. Compatibilidad de revisión pendiente de fabricante.","Todas las alturas parciales son hipótesis de visualización; solo la altura total de 3,38 m está acotada.","Las regiones del dibujo se usan como envolventes de cuerpos; la identificación funcional y la cota Z de cada pieza requieren verificación.","Pequeños taladros, tornillería y detalles interiores de las regiones no se extruyen como vacíos de fabricación.","El bastidor documentado mide 2,35 × 5,22 m. Los accesorios del detalle de abril sobresalen; el conjunto refinado ocupa aproximadamente 2,596 × 6,268 m en ejes del fabricante, pendiente de coordinación entre revisiones.","El acabado de grout HA-35 de 50 mm termina en +0,400; el hormigón termina en +0,350. La losa MAC contigua termina en +0,200.","El cero absoluto de la revisión no está definido; 286,10 m sigue siendo una hipótesis de coordinación.","Se alinea el punto inferior del conjunto del equipo, incluidos los pies ya representados, con la superficie de apoyo terminada; no se añade un espesor de calzos, placa o grout del fabricante no documentado."] | {"revision":"Detalle en planta de 2026-04-30 coordinado de forma preliminar con envolventes y alturas de 2026-08-25","status":"provisional","verticalRule":"Altura total documentada: 3,38 m. Plataforma gráfica de 0,15 m; los cuerpos extraídos de la planta reciben alturas provisionales entre 1,00 y 3,38 m, detalladas por subvolumen. No se dispone de alzado acotado de cada componente.","partCount":26,"source":{"documentId":"EQ-IMPLANTACION-20260430","title":"Plano del fabricante: implantación de equipos","sheet":"LHD2609-GD01000 · espacio modelo","date":"2026-04-30"},"heightSource":{"documentId":"EQ-CARGAS-20260825","title":"Plano del fabricante: cargas de equipos","sheet":"Espacio modelo","date":"2026-08-25"},"unconfirmedDimensions":["Todas las alturas parciales son hipótesis de visualización; solo la altura total de 3,38 m está acotada.","Las regiones del dibujo se usan como envolventes de cuerpos; la identificación funcional y la cota Z de cada pieza requieren verificación.","Pequeños taladros, tornillería y detalles interiores de las regiones no se extruyen como vacíos de fabricación."],"quantityUse":"Magnitudes de la geometría representada; no son cantidades de material, obra, compra, capacidad útil ni fabricación. En geometrías compuestas se suman superficies y volúmenes de partes y pueden existir solapes no depurados.","partsAreBOM":false} | equipment_component | {"min":[54.480044,69.250118,1.5],"max":[57.657628,75.654646,4.88]} | {"boundingBoxM":{"min":[54.480044,69.250118,1.5],"max":[57.657628,75.654646,4.88]},"extentsM":[3.177584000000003,6.404527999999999,3.38],"meshSurfaceM2":165.19823454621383,"meshVolumeM3":20.17010370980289,"closedSolid":true,"windingConsistent":true,"basis":"Submalla exacta de los triángulos del modelo IFC coordinado; separación de componentes sin transformación ni retesselación."} | ["Todas las alturas parciales son hipótesis de visualización; solo la altura total de 3,38 m está acotada.","Las regiones del dibujo se usan como envolventes de cuerpos; la identificación funcional y la cota Z de cada pieza requieren verificación.","Pequeños taladros, tornillería y detalles interiores de las regiones no se extruyen como vacíos de fabricación.","La separación gráfica no aporta cotas de fabricación ni identifica piezas internas no documentadas.","Los materiales y acabados permanecen provisionales; las fotografías públicas solo orientan la apariencia."] | {"id":"AC1001B--base","sourcePartId":"AC1001B--base","name":"Envolvente del bastidor de referencia","role":"equipment_component","classificationStatus":"provisional","classificationBasis":"Rol del subvolumen gráfico según el activo de detalle; identidad de fabricación no confirmada.","parentEquipmentId":"AC1001B","parentEquipmentGuid":"1IHLxwSiXVEvsMWIfO71jb","isAssemblyIdentityCarrier":false,"sourceFaceRange":[0,12],"sourceCurrentFaceIndices":[0,1,2,3,4,5,6,7,8,9,10,11],"sourceMeshSha256":"7b60c904c9d84d22fded9be34af09a09a9c198ec8e75e61902634d5e4064c761","sourceVertexIndices":[0,1,2,3,4,5,6,7],"separationMethod":"Partición exacta de triángulos existentes; coordenadas y orientación de caras conservadas.","quantityUse":"Magnitudes geométricas del subvolumen; no son cantidades netas de material, fabricación, suministro o capacidad."} | {"id":"AC1001B","name":"Compresor de aire AC1001B","relationship":"decomposed_component","parentShapeMeaning":"La forma del objeto que conserva el ID del equipo es únicamente su componente principal; el conjunto completo requiere sus hijos."} | {"kind":"through_parent","parentEquipmentId":"AC1001B","directAnchorageVerified":false,"note":"La relación del conjunto con cimentaciones se conserva en el objeto que mantiene el ID del equipo; no se atribuye fijación directa a cada subcomponente."} | Documento de implantación y apoyo del conjunto padre; no acredita fijación individual de este componente. | AC1001B--base | Envolvente del bastidor de referencia | Equipos | unknown | equipment_dark_frame | {"documentId":"EQ-CARGAS-20260825","title":"Plano del fabricante: cargas de equipos","sheet":"Espacio modelo","date":"2026-08-25","componentSourceHandles":["3ED"]} | Submalla de triángulos existentes; no hay nueva posición ni nuevas caras. | Cotas globales del conjunto conservadas aparte; las dimensiones de esta ficha son de la submalla. | Coordinación del conjunto padre; anclaje directo individual no acreditado. | Superficie y volumen geométricos brutos; no constituyen cantidades netas de obra, material o fabricación. | Plano general y dimensiones globales de AC1001B; no se asignan esas dimensiones globales a este componente. | ["3ED"] | 1 | no | Submalla exacta; interpretación funcional y cotas parciales provisionales.
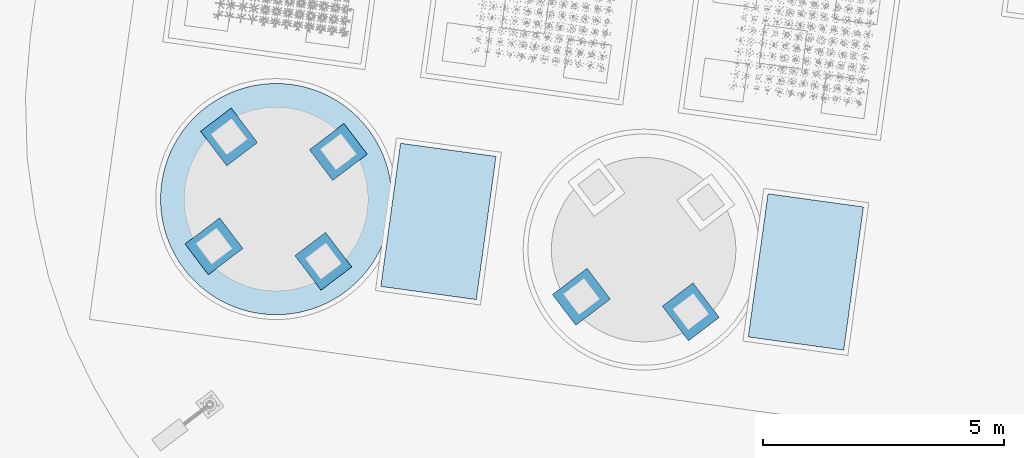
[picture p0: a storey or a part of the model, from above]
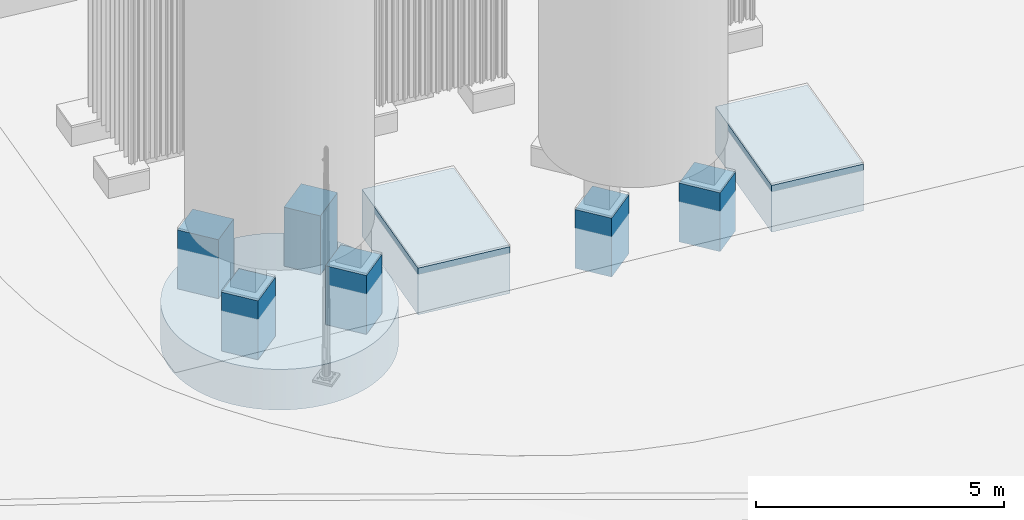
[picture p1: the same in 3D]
Properties of the parts of a building model (IFC4), part 39 of 134

# IfcBuildingElementProxy (140)
Name | Description | Document | Extensión de la malla en X (m) = ExtensionX (m) | Extensión de la malla en Y (m) = ExtensionY (m) | Extensión de la malla en Z (m) = ExtensionZ (m) | Cota inferior de visualización (m) | Cota superior de visualización (m) | SuperficieDeLaMalla (m2) | VolumenGeometrico (m3) | level | category = Categoria = Funcion | representationKind | material | dimensions | JH_InformacionBIM, source = DocumentoFuente | positioning = PosicionYEstado | issues | detailGeometry | geometryMetrics | installationSource | layerId = IdentificadorCapa | visualLayer | materialAppearance | componentSeparation | visualizationIdentity | classification | appearance | Disciplina | Material | Capa BIM = NombreCapa | Acabado de visualización = Acabado | Estado del acabado = Estado | Identificador | JH_Trazabilidad, IncidenciasPendientes | UsoDeLasMagnitudes | JH_EvidenciaDeMaterial, source | JH_DetalleGeometrico, source | VisibilidadInicial | Perfil | ColorRGB | Rugosidad | Metallicidad | Referencia | Nota | Group | parentEquipmentId = Identificador del equipo padre | parentEquipmentName = Equipo padre | parentEquipmentIfcClass | parentEquipmentDimensions | parentEquipmentPositioning | parentEquipmentIssues | parentEquipmentDetail | componentRole = Rol del componente | assemblyBBox | assemblyGeometryMetrics | manufacturerDetailsPending | component | assembly | foundationRelationship | installationSourceScope | Identificador del elemento = sourcePartId | Componente | Capa de visualización | Estado del material | Perfil visual del material | Fuente del componente | Criterio de partición | Criterio de las dimensiones | Relación con cimentaciones | Aplicabilidad de las mediciones | Referencia dimensional del conjunto | sourceHandles | partCount | partsAreBOM | status
Compresor de aire AC1001B · Cuerpo de equipo · región CAD 20 | Componente de equipo · cuerpo o accesorio | Plano del fabricante: implantación de equipos · referencia E7 | 0.437979 | 0.347682 | 2.4 | 286.65 | 289.05 | 4.13118 | 0.131247 | Apoyo relativo +0.400 m; cero absoluto provisional | Componente de equipo · cuerpo o accesorio | equipmentComponent | {"name":"No especificado","source":"Sin especificación de material en la documentación revisada","status":"unknown"} | {"documented":[{"label":"Referencia dimensional del conjunto","value":"Plano general y dimensiones globales de AC1001B; no se asignan esas dimensiones globales a este componente.","unit":"","source":"EQ-IMPLANTACION-20260430 · LHD2609-GD01000 · espacio modelo","status":"referencia_del_conjunto"}],"geometry":[{"label":"Extensión de la malla en X","value":0.43797899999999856,"unit":"m","source":"Geometría releída del IFC; datum absoluto de proceso provisional","status":"derivado"},{"label":"Extensión de la malla en Y","value":0.34768200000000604,"unit":"m","source":"Geometría releída del IFC; datum absoluto de proceso provisional","status":"derivado"},{"label":"Extensión de la malla en Z","value":2.4,"unit":"m","source":"Geometría releída del IFC; datum absoluto de proceso provisional","status":"derivado"},{"label":"Cota inferior de visualización","value":286.65,"unit":"m","source":"Geometría releída del IFC; datum absoluto de proceso provisional","status":"derivado"},{"label":"Cota superior de visualización","value":289.05,"unit":"m","source":"Geometría releída del IFC; datum absoluto de proceso provisional","status":"derivado"}],"notes":["Las dimensiones del equipo completo se conservan en parentEquipmentDimensions.","Las extensiones en X/Y son de los ejes del modelo y no sustituyen cotas locales de fabricación.","No se infieren espesores de chapa, tolerancias ni dimensiones de piezas a partir de la partición."]} | {"documentId":"EQ-IMPLANTACION-20260430","title":"Plano del fabricante: implantación de equipos","sheet":"LHD2609-GD01000 · espacio modelo","date":"2026-04-30","componentSourceHandles":["7134D","71625","71657","71658","71659","7165A","7165C","7165D","7165F","71684","71711","71712","71713","71714","7171D","7171E","7171F","71720","71721","71722","71723","71724","71725","71727","71728","71729","7172A","7172B","7172F","71731","71732","71733","7173D","7173E","7173F","71740","717D3","717FA","717FC","71907","71981","71A0F","71A13","71A3C"]} | {"horizontalStatus":"derivado_del_conjunto","verticalStatus":"derivado_del_conjunto","coordinateSystem":"model_local_m","parentEquipmentId":"AC1001B","transformApplied":false,"note":"Coordenadas copiadas exactamente del equipo coordinado; no se ha movido, girado, elevado ni reescalado este componente.","foundationRelationship":"El apoyo y las cotas de instalación se documentan para el conjunto padre. Esta submalla no acredita un anclaje directo.","meshMinimumAbsoluteElevationM":286.65,"assemblyPlacementField":"parentEquipmentPositioning"} | ["Componente separado de una reconstrucción documental del conjunto. Las alturas y detalles parciales conservan las limitaciones del fabricante registradas en parentEquipmentIssues.","Esta representación exterior no crea una chapa hueca ni añade componentes internos no documentados.","La pertenencia al conjunto no demuestra apoyo o anclaje directo a la cimentación."] | {"source":{"documentId":"EQ-IMPLANTACION-20260430","title":"Plano del fabricante: implantación de equipos","sheet":"LHD2609-GD01000 · espacio modelo","date":"2026-04-30","componentSourceHandles":["7134D","71625","71657","71658","71659","7165A","7165C","7165D","7165F","71684","71711","71712","71713","71714","7171D","7171E","7171F","71720","71721","71722","71723","71724","71725","71727","71728","71729","7172A","7172B","7172F","71731","71732","71733","7173D","7173E","7173F","71740","717D3","717FA","717FC","71907","71981","71A0F","71A13","71A3C"]},"sourcePartId":"AC1001B--cad-region-020","sourceHandles":["7134D","71625","71657","71658","71659","7165A","7165C","7165D","7165F","71684","71711","71712","71713","71714","7171D","7171E","7171F","71720","71721","71722","71723","71724","71725","71727","71728","71729","7172A","7172B","7172F","71731","71732","71733","7173D","7173E","7173F","71740","717D3","717FA","717FC","71907","71981","71A0F","71A13","71A3C"],"partCount":1,"partsAreBOM":false,"status":"Submalla exacta; interpretación funcional y cotas parciales provisionales."} | {"boundingBoxM":{"min":[55.999479,74.037303,1.65],"max":[56.437458,74.384985,4.05]},"extentsM":[0.437979,0.347682,2.4],"meshSurfaceM2":4.131177,"meshVolumeM3":0.131247,"closedSolid":true,"basis":"Geometría de coordinación. Los volúmenes de referencia y subcomponentes no son cantidades de material ni componentes de fabricación certificados."} | {"documentId":"LHD2609-JG00100-20260904","title":"Cimentaciones y pedestales de equipos · revisión recibida 04/09/2026","date":"2026-09-04","sheet":"1 / 1-1","sourceHandles":["28C35","28C38","28C3B","28C89"]} | equipment | {"id":"equipment","name":"Equipos"} | {"profileId":"equipment_light_gray","name":"Equipo · gris claro provisional","materialName":"No especificado","physicalMaterialStatus":"unknown","physicalMaterialSource":"Sin especificación de material en la documentación revisada","appearanceStatus":"provisional","appearanceBasis":"Referencia visual de fotografías públicas de Jinhong Gas / fabricante. Apariencia provisional para coordinación; fotografías oficiales pueden orientar el color, pero no acreditan el material, el acabado ni el equipo concreto.","appearanceReferences":["jinhong-official-asu"],"note":"El perfil visual no confirma material, grado ni acabado del componente."} | {"status":"componente_independiente","note":"Objeto independiente seleccionable. Las caras se asignan una sola vez entre todos los componentes del conjunto.","parentEquipmentId":"AC1001B","isAssemblyIdentityCarrier":false} | {"elementId":"AC1001B--cad-region-020","ifcGuid":"1qf5G08VXPqwEPsqT1CdOF","ifcClass":"IfcBuildingElementProxy","buildingId":"process_plant","buildingName":"Planta de proceso","sourceDocumentId":"EQ-IMPLANTACION-20260430","sourceRepresentationKind":"equipmentComponent"} | {"layerId":"equipment","layerName":"Equipos","role":"Componente de equipo · cuerpo o accesorio","basis":"Clasificación por función del elemento; no modifica las especificaciones documentales."} | {"profileId":"equipment_light_gray","name":"Equipo · gris claro provisional","status":"provisional","basis":"Referencia visual de fotografías públicas de Jinhong Gas / fabricante. Apariencia provisional para coordinación; fotografías oficiales pueden orientar el color, pero no acreditan el material, el acabado ni el equipo concreto.","physicalMaterialUnchanged":true} | Equipos | No especificado | Equipos | Equipo · gris claro provisional | provisional | AC1001B--cad-region-020 | ["Componente separado de una reconstrucción documental del conjunto. Las alturas y detalles parciales conservan las limitaciones del fabricante registradas en parentEquipmentIssues.","Esta representación exterior no crea una chapa hueca ni añade componentes internos no documentados.","La pertenencia al conjunto no demuestra apoyo o anclaje directo a la cimentación."] | Geometría de coordinación. Los volúmenes de referencia y subcomponentes no son cantidades de material ni componentes de fabricación certificados. | Sin especificación de material en la documentación revisada | {"documentId":"EQ-IMPLANTACION-20260430","title":"Plano del fabricante: implantación de equipos","sheet":"LHD2609-GD01000 · espacio modelo","date":"2026-04-30","componentSourceHandles":["7134D","71625","71657","71658","71659","7165A","7165C","7165D","7165F","71684","71711","71712","71713","71714","7171D","7171E","7171F","71720","71721","71722","71723","71724","71725","71727","71728","71729","7172A","7172B","7172F","71731","71732","71733","7173D","7173E","7173F","71740","717D3","717FA","717FC","71907","71981","71A0F","71A13","71A3C"]} | yes | equipment_light_gray | [0.88,0.89,0.88] | 0.45 | 0.28 | Referencia visual de fotografías públicas de Jinhong Gas / fabricante. Apariencia provisional para coordinación; fotografías oficiales pueden orientar el color, pero no acreditan el material, el acabado ni el equipo concreto. | La apariencia no certifica el material físico ni el acabado de fabricación. | BIM · Equipos | AC1001B | Compresor de aire AC1001B | IfcCompressor | {"documented":[{"label":"Dimensión X local del bastidor de referencia CAD","value":2.35,"unit":"m","source":"EQ-CARGAS-20260825 · contorno CAD · handles 3ED","status":"derivado"},{"label":"Dimensión Y local del bastidor de referencia CAD","value":5.22,"unit":"m","source":"EQ-CARGAS-20260825 · contorno CAD · handles 3ED","status":"derivado"},{"label":"Altura acotada","value":3.38,"unit":"m","source":"EQ-CARGAS-20260825 · handle 25A3","status":"documentado"},{"label":"Cota relativa de la superficie de apoyo","value":0.4,"unit":"m","source":"LHD2609-JG00100-20260904 · sección 1 / 1-1 · 28C35, 28C38, 28C3B, 28C89","status":"documentado"}],"geometry":[{"label":"Extensión de la malla en X","value":3.177584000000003,"unit":"m","source":"Geometría releída del IFC; datum absoluto de proceso provisional","status":"derivado"},{"label":"Extensión de la malla en Y","value":6.404527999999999,"unit":"m","source":"Geometría releída del IFC; datum absoluto de proceso provisional","status":"derivado"},{"label":"Extensión de la malla en Z","value":3.3800000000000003,"unit":"m","source":"Geometría releída del IFC; datum absoluto de proceso provisional","status":"derivado"},{"label":"Cota inferior de visualización","value":286.5,"unit":"m","source":"Geometría releída del IFC; datum absoluto de proceso provisional","status":"derivado"},{"label":"Cota superior de visualización","value":289.88,"unit":"m","source":"Geometría releída del IFC; datum absoluto de proceso provisional","status":"derivado"}],"notes":["Las extensiones de la malla se miden en los ejes del proyecto tras el giro de implantación; no sustituyen las dimensiones locales del fabricante.","La envolvente, su volumen y los espesores de visualización no son volúmenes de material ni cantidades de compra, construcción o fabricación.","Las dimensiones documentadas distinguen cotas explícitas y medidas extraídas de contornos CAD; las dimensiones geométricas describen únicamente la malla publicada.","Las extensiones de la malla refinada y las dimensiones documentadas del contorno o bastidor tienen distinto alcance; las cotas parciales del detalle son provisionales."]} | {"Estado de la planta":"Derivado del CAD y del giro de implantación","Nivel relativo del apoyo (m)":0.4,"Estado del nivel relativo":"Documentado en el plano de cimentaciones","Cero absoluto de visualización (m)":286.1,"Estado del cero absoluto":"Provisional","Cota del apoyo de visualización (m)":286.5,"Desplazamiento aplicado a la malla (m)":0.40000000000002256,"Criterio":"Nivel de apoyo relativo documentado. Se adopta el cero de proceso a 286,10 m solo para visualización; la equivalencia absoluta no está confirmada. No se añade un espesor de montaje sin cota del fabricante."} | ["La máquina está contenida en la envolvente de la cabina acústica; su superposición no acredita una interferencia física.","El bastidor CAD coincide con la referencia de 2,35 × 5,22 m del plano de cargas, pero cuerpos y auxiliares del detalle de abril sobresalen de esa referencia, hasta aproximadamente 1,048 m por el extremo sur y 0,246 m por el lado oeste. Extensión geométrica resultante: 2,595899 × 6,268101 × 3,38 m, derivada y pendiente de coordinación entre revisiones. Permanecen dentro de la cabina acústica. Compatibilidad de revisión pendiente de fabricante.","Todas las alturas parciales son hipótesis de visualización; solo la altura total de 3,38 m está acotada.","Las regiones del dibujo se usan como envolventes de cuerpos; la identificación funcional y la cota Z de cada pieza requieren verificación.","Pequeños taladros, tornillería y detalles interiores de las regiones no se extruyen como vacíos de fabricación.","El bastidor documentado mide 2,35 × 5,22 m. Los accesorios del detalle de abril sobresalen; el conjunto refinado ocupa aproximadamente 2,596 × 6,268 m en ejes del fabricante, pendiente de coordinación entre revisiones.","El acabado de grout HA-35 de 50 mm termina en +0,400; el hormigón termina en +0,350. La losa MAC contigua termina en +0,200.","El cero absoluto de la revisión no está definido; 286,10 m sigue siendo una hipótesis de coordinación.","Se alinea el punto inferior del conjunto del equipo, incluidos los pies ya representados, con la superficie de apoyo terminada; no se añade un espesor de calzos, placa o grout del fabricante no documentado."] | {"revision":"Detalle en planta de 2026-04-30 coordinado de forma preliminar con envolventes y alturas de 2026-08-25","status":"provisional","verticalRule":"Altura total documentada: 3,38 m. Plataforma gráfica de 0,15 m; los cuerpos extraídos de la planta reciben alturas provisionales entre 1,00 y 3,38 m, detalladas por subvolumen. No se dispone de alzado acotado de cada componente.","partCount":26,"source":{"documentId":"EQ-IMPLANTACION-20260430","title":"Plano del fabricante: implantación de equipos","sheet":"LHD2609-GD01000 · espacio modelo","date":"2026-04-30"},"heightSource":{"documentId":"EQ-CARGAS-20260825","title":"Plano del fabricante: cargas de equipos","sheet":"Espacio modelo","date":"2026-08-25"},"unconfirmedDimensions":["Todas las alturas parciales son hipótesis de visualización; solo la altura total de 3,38 m está acotada.","Las regiones del dibujo se usan como envolventes de cuerpos; la identificación funcional y la cota Z de cada pieza requieren verificación.","Pequeños taladros, tornillería y detalles interiores de las regiones no se extruyen como vacíos de fabricación."],"quantityUse":"Magnitudes de la geometría representada; no son cantidades de material, obra, compra, capacidad útil ni fabricación. En geometrías compuestas se suman superficies y volúmenes de partes y pueden existir solapes no depurados.","partsAreBOM":false} | equipment_component | {"min":[54.480044,69.250118,1.5],"max":[57.657628,75.654646,4.88]} | {"boundingBoxM":{"min":[54.480044,69.250118,1.5],"max":[57.657628,75.654646,4.88]},"extentsM":[3.177584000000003,6.404527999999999,3.38],"meshSurfaceM2":165.19823454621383,"meshVolumeM3":20.17010370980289,"closedSolid":true,"windingConsistent":true,"basis":"Submalla exacta de los triángulos del modelo IFC coordinado; separación de componentes sin transformación ni retesselación."} | ["Todas las alturas parciales son hipótesis de visualización; solo la altura total de 3,38 m está acotada.","Las regiones del dibujo se usan como envolventes de cuerpos; la identificación funcional y la cota Z de cada pieza requieren verificación.","Pequeños taladros, tornillería y detalles interiores de las regiones no se extruyen como vacíos de fabricación.","La separación gráfica no aporta cotas de fabricación ni identifica piezas internas no documentadas.","Los materiales y acabados permanecen provisionales; las fotografías públicas solo orientan la apariencia."] | {"id":"AC1001B--cad-region-020","sourcePartId":"AC1001B--cad-region-020","name":"Cuerpo de equipo · región CAD 20","role":"equipment_component","classificationStatus":"provisional","classificationBasis":"Rol del subvolumen gráfico según el activo de detalle; identidad de fabricación no confirmada.","parentEquipmentId":"AC1001B","parentEquipmentGuid":"1IHLxwSiXVEvsMWIfO71jb","isAssemblyIdentityCarrier":false,"sourceFaceRange":[1372,1536],"sourceCurrentFaceIndices":[1372,1373,1374,1375,1376,1377,1378,1379,1380,1381,1382,1383,1384,1385,1386,1387,1388,1389,1390,1391,1392,1393,1394,1395,1396,1397,1398,1399,1400,1401,1402,1403,1404,1405,1406,1407,1408,1409,1410,1411,1412,1413,1414,1415,1416,1417,1418,1419,1420,1421,1422,1423,1424,1425,1426,1427,1428,1429,1430,1431,1432,1433,1434,1435,1436,1437,1438,1439,1440,1441,1442,1443,1444,1445,1446,1447,1448,1449,1450,1451,1452,1453,1454,1455,1456,1457,1458,1459,1460,1461,1462,1463,1464,1465,1466,1467,1468,1469,1470,1471,1472,1473,1474,1475,1476,1477,1478,1479,1480,1481,1482,1483,1484,1485,1486,1487,1488,1489,1490,1491,1492,1493,1494,1495,1496,1497,1498,1499,1500,1501,1502,1503,1504,1505,1506,1507,1508,1509,1510,1511,1512,1513,1514,1515,1516,1517,1518,1519,1520,1521,1522,1523,1524,1525,1526,1527,1528,1529,1530,1531,1532,1533,1534,1535],"sourceMeshSha256":"7b60c904c9d84d22fded9be34af09a09a9c198ec8e75e61902634d5e4064c761","sourceVertexIndices":[722,723,724,725,726,727,728,729,730,731,732,733,734,735,736,737,738,739,740,741,742,743,744,745,746,747,748,749,750,751,752,753,754,755,756,757,758,759,760,761,762,763,764,765,766,767,768,769,770,771,772,773,774,775,776,777,778,779,780,781,782,783,784,785,786,787,788,789,790,791,792,793,794,795,796,797,798,799,800,801,802,803,804,805],"separationMethod":"Partición exacta de triángulos existentes; coordenadas y orientación de caras conservadas.","quantityUse":"Magnitudes geométricas del subvolumen; no son cantidades netas de material, fabricación, suministro o capacidad."} | {"id":"AC1001B","name":"Compresor de aire AC1001B","relationship":"decomposed_component","parentShapeMeaning":"La forma del objeto que conserva el ID del equipo es únicamente su componente principal; el conjunto completo requiere sus hijos."} | {"kind":"through_parent","parentEquipmentId":"AC1001B","directAnchorageVerified":false,"note":"La relación del conjunto con cimentaciones se conserva en el objeto que mantiene el ID del equipo; no se atribuye fijación directa a cada subcomponente."} | Documento de implantación y apoyo del conjunto padre; no acredita fijación individual de este componente. | AC1001B--cad-region-020 | Cuerpo de equipo · región CAD 20 | Equipos | unknown | equipment_light_gray | {"documentId":"EQ-IMPLANTACION-20260430","title":"Plano del fabricante: implantación de equipos","sheet":"LHD2609-GD01000 · espacio modelo","date":"2026-04-30","componentSourceHandles":["7134D","71625","71657","71658","71659","7165A","7165C","7165D","7165F","71684","71711","71712","71713","71714","7171D","7171E","7171F","71720","71721","71722","71723","71724","71725","71727","71728","71729","7172A","7172B","7172F","71731","71732","71733","7173D","7173E","7173F","71740","717D3","717FA","717FC","71907","71981","71A0F","71A13","71A3C"]} | Submalla de triángulos existentes; no hay nueva posición ni nuevas caras. | Cotas globales del conjunto conservadas aparte; las dimensiones de esta ficha son de la submalla. | Coordinación del conjunto padre; anclaje directo individual no acreditado. | Superficie y volumen geométricos brutos; no constituyen cantidades netas de obra, material o fabricación. | Plano general y dimensiones globales de AC1001B; no se asignan esas dimensiones globales a este componente. | ["7134D","71625","71657","71658","71659","7165A","7165C","7165D","7165F","71684","71711","71712","71713","71714","7171D","7171E","7171F","71720","71721","71722","71723","71724","71725","71727","71728","71729","7172A","7172B","7172F","71731","71732","71733","7173D","7173E","7173F","71740","717D3","717FA","717FC","71907","71981","71A0F","71A13","71A3C"] | 1 | no | Submalla exacta; interpretación funcional y cotas parciales provisionales.
Compresor de aire AC1001B · Cuerpo de equipo · región CAD 24 | Componente de equipo · cuerpo o accesorio | Plano del fabricante: implantación de equipos · referencia E7 | 0.355285 | 0.166324 | 2.35 | 286.65 | 289 | 2.25309 | 0.097086 | Apoyo relativo +0.400 m; cero absoluto provisional | Componente de equipo · cuerpo o accesorio | equipmentComponent | {"name":"No especificado","source":"Sin especificación de material en la documentación revisada","status":"unknown"} | {"documented":[{"label":"Referencia dimensional del conjunto","value":"Plano general y dimensiones globales de AC1001B; no se asignan esas dimensiones globales a este componente.","unit":"","source":"EQ-IMPLANTACION-20260430 · LHD2609-GD01000 · espacio modelo","status":"referencia_del_conjunto"}],"geometry":[{"label":"Extensión de la malla en X","value":0.35528500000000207,"unit":"m","source":"Geometría releída del IFC; datum absoluto de proceso provisional","status":"derivado"},{"label":"Extensión de la malla en Y","value":0.16632400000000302,"unit":"m","source":"Geometría releída del IFC; datum absoluto de proceso provisional","status":"derivado"},{"label":"Extensión de la malla en Z","value":2.35,"unit":"m","source":"Geometría releída del IFC; datum absoluto de proceso provisional","status":"derivado"},{"label":"Cota inferior de visualización","value":286.65,"unit":"m","source":"Geometría releída del IFC; datum absoluto de proceso provisional","status":"derivado"},{"label":"Cota superior de visualización","value":289.0,"unit":"m","source":"Geometría releída del IFC; datum absoluto de proceso provisional","status":"derivado"}],"notes":["Las dimensiones del equipo completo se conservan en parentEquipmentDimensions.","Las extensiones en X/Y son de los ejes del modelo y no sustituyen cotas locales de fabricación.","No se infieren espesores de chapa, tolerancias ni dimensiones de piezas a partir de la partición."]} | {"documentId":"EQ-IMPLANTACION-20260430","title":"Plano del fabricante: implantación de equipos","sheet":"LHD2609-GD01000 · espacio modelo","date":"2026-04-30","componentSourceHandles":["7134F","71355","71DB1","72F08","72F0B","72F10","72F11"]} | {"horizontalStatus":"derivado_del_conjunto","verticalStatus":"derivado_del_conjunto","coordinateSystem":"model_local_m","parentEquipmentId":"AC1001B","transformApplied":false,"note":"Coordenadas copiadas exactamente del equipo coordinado; no se ha movido, girado, elevado ni reescalado este componente.","foundationRelationship":"El apoyo y las cotas de instalación se documentan para el conjunto padre. Esta submalla no acredita un anclaje directo.","meshMinimumAbsoluteElevationM":286.65,"assemblyPlacementField":"parentEquipmentPositioning"} | ["Componente separado de una reconstrucción documental del conjunto. Las alturas y detalles parciales conservan las limitaciones del fabricante registradas en parentEquipmentIssues.","Esta representación exterior no crea una chapa hueca ni añade componentes internos no documentados.","La pertenencia al conjunto no demuestra apoyo o anclaje directo a la cimentación."] | {"source":{"documentId":"EQ-IMPLANTACION-20260430","title":"Plano del fabricante: implantación de equipos","sheet":"LHD2609-GD01000 · espacio modelo","date":"2026-04-30","componentSourceHandles":["7134F","71355","71DB1","72F08","72F0B","72F10","72F11"]},"sourcePartId":"AC1001B--cad-region-024","sourceHandles":["7134F","71355","71DB1","72F08","72F0B","72F10","72F11"],"partCount":1,"partsAreBOM":false,"status":"Submalla exacta; interpretación funcional y cotas parciales provisionales."} | {"boundingBoxM":{"min":[56.650867,74.390881,1.65],"max":[57.006152,74.557205,4.0]},"extentsM":[0.355285,0.166324,2.35],"meshSurfaceM2":2.253087,"meshVolumeM3":0.097086,"closedSolid":true,"basis":"Geometría de coordinación. Los volúmenes de referencia y subcomponentes no son cantidades de material ni componentes de fabricación certificados."} | {"documentId":"LHD2609-JG00100-20260904","title":"Cimentaciones y pedestales de equipos · revisión recibida 04/09/2026","date":"2026-09-04","sheet":"1 / 1-1","sourceHandles":["28C35","28C38","28C3B","28C89"]} | equipment | {"id":"equipment","name":"Equipos"} | {"profileId":"equipment_light_gray","name":"Equipo · gris claro provisional","materialName":"No especificado","physicalMaterialStatus":"unknown","physicalMaterialSource":"Sin especificación de material en la documentación revisada","appearanceStatus":"provisional","appearanceBasis":"Referencia visual de fotografías públicas de Jinhong Gas / fabricante. Apariencia provisional para coordinación; fotografías oficiales pueden orientar el color, pero no acreditan el material, el acabado ni el equipo concreto.","appearanceReferences":["jinhong-official-asu"],"note":"El perfil visual no confirma material, grado ni acabado del componente."} | {"status":"componente_independiente","note":"Objeto independiente seleccionable. Las caras se asignan una sola vez entre todos los componentes del conjunto.","parentEquipmentId":"AC1001B","isAssemblyIdentityCarrier":false} | {"elementId":"AC1001B--cad-region-024","ifcGuid":"3HNP3X$xfMGxnGM8AgmC$i","ifcClass":"IfcBuildingElementProxy","buildingId":"process_plant","buildingName":"Planta de proceso","sourceDocumentId":"EQ-IMPLANTACION-20260430","sourceRepresentationKind":"equipmentComponent"} | {"layerId":"equipment","layerName":"Equipos","role":"Componente de equipo · cuerpo o accesorio","basis":"Clasificación por función del elemento; no modifica las especificaciones documentales."} | {"profileId":"equipment_light_gray","name":"Equipo · gris claro provisional","status":"provisional","basis":"Referencia visual de fotografías públicas de Jinhong Gas / fabricante. Apariencia provisional para coordinación; fotografías oficiales pueden orientar el color, pero no acreditan el material, el acabado ni el equipo concreto.","physicalMaterialUnchanged":true} | Equipos | No especificado | Equipos | Equipo · gris claro provisional | provisional | AC1001B--cad-region-024 | ["Componente separado de una reconstrucción documental del conjunto. Las alturas y detalles parciales conservan las limitaciones del fabricante registradas en parentEquipmentIssues.","Esta representación exterior no crea una chapa hueca ni añade componentes internos no documentados.","La pertenencia al conjunto no demuestra apoyo o anclaje directo a la cimentación."] | Geometría de coordinación. Los volúmenes de referencia y subcomponentes no son cantidades de material ni componentes de fabricación certificados. | Sin especificación de material en la documentación revisada | {"documentId":"EQ-IMPLANTACION-20260430","title":"Plano del fabricante: implantación de equipos","sheet":"LHD2609-GD01000 · espacio modelo","date":"2026-04-30","componentSourceHandles":["7134F","71355","71DB1","72F08","72F0B","72F10","72F11"]} | yes | equipment_light_gray | [0.88,0.89,0.88] | 0.45 | 0.28 | Referencia visual de fotografías públicas de Jinhong Gas / fabricante. Apariencia provisional para coordinación; fotografías oficiales pueden orientar el color, pero no acreditan el material, el acabado ni el equipo concreto. | La apariencia no certifica el material físico ni el acabado de fabricación. | BIM · Equipos | AC1001B | Compresor de aire AC1001B | IfcCompressor | {"documented":[{"label":"Dimensión X local del bastidor de referencia CAD","value":2.35,"unit":"m","source":"EQ-CARGAS-20260825 · contorno CAD · handles 3ED","status":"derivado"},{"label":"Dimensión Y local del bastidor de referencia CAD","value":5.22,"unit":"m","source":"EQ-CARGAS-20260825 · contorno CAD · handles 3ED","status":"derivado"},{"label":"Altura acotada","value":3.38,"unit":"m","source":"EQ-CARGAS-20260825 · handle 25A3","status":"documentado"},{"label":"Cota relativa de la superficie de apoyo","value":0.4,"unit":"m","source":"LHD2609-JG00100-20260904 · sección 1 / 1-1 · 28C35, 28C38, 28C3B, 28C89","status":"documentado"}],"geometry":[{"label":"Extensión de la malla en X","value":3.177584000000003,"unit":"m","source":"Geometría releída del IFC; datum absoluto de proceso provisional","status":"derivado"},{"label":"Extensión de la malla en Y","value":6.404527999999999,"unit":"m","source":"Geometría releída del IFC; datum absoluto de proceso provisional","status":"derivado"},{"label":"Extensión de la malla en Z","value":3.3800000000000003,"unit":"m","source":"Geometría releída del IFC; datum absoluto de proceso provisional","status":"derivado"},{"label":"Cota inferior de visualización","value":286.5,"unit":"m","source":"Geometría releída del IFC; datum absoluto de proceso provisional","status":"derivado"},{"label":"Cota superior de visualización","value":289.88,"unit":"m","source":"Geometría releída del IFC; datum absoluto de proceso provisional","status":"derivado"}],"notes":["Las extensiones de la malla se miden en los ejes del proyecto tras el giro de implantación; no sustituyen las dimensiones locales del fabricante.","La envolvente, su volumen y los espesores de visualización no son volúmenes de material ni cantidades de compra, construcción o fabricación.","Las dimensiones documentadas distinguen cotas explícitas y medidas extraídas de contornos CAD; las dimensiones geométricas describen únicamente la malla publicada.","Las extensiones de la malla refinada y las dimensiones documentadas del contorno o bastidor tienen distinto alcance; las cotas parciales del detalle son provisionales."]} | {"Estado de la planta":"Derivado del CAD y del giro de implantación","Nivel relativo del apoyo (m)":0.4,"Estado del nivel relativo":"Documentado en el plano de cimentaciones","Cero absoluto de visualización (m)":286.1,"Estado del cero absoluto":"Provisional","Cota del apoyo de visualización (m)":286.5,"Desplazamiento aplicado a la malla (m)":0.40000000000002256,"Criterio":"Nivel de apoyo relativo documentado. Se adopta el cero de proceso a 286,10 m solo para visualización; la equivalencia absoluta no está confirmada. No se añade un espesor de montaje sin cota del fabricante."} | ["La máquina está contenida en la envolvente de la cabina acústica; su superposición no acredita una interferencia física.","El bastidor CAD coincide con la referencia de 2,35 × 5,22 m del plano de cargas, pero cuerpos y auxiliares del detalle de abril sobresalen de esa referencia, hasta aproximadamente 1,048 m por el extremo sur y 0,246 m por el lado oeste. Extensión geométrica resultante: 2,595899 × 6,268101 × 3,38 m, derivada y pendiente de coordinación entre revisiones. Permanecen dentro de la cabina acústica. Compatibilidad de revisión pendiente de fabricante.","Todas las alturas parciales son hipótesis de visualización; solo la altura total de 3,38 m está acotada.","Las regiones del dibujo se usan como envolventes de cuerpos; la identificación funcional y la cota Z de cada pieza requieren verificación.","Pequeños taladros, tornillería y detalles interiores de las regiones no se extruyen como vacíos de fabricación.","El bastidor documentado mide 2,35 × 5,22 m. Los accesorios del detalle de abril sobresalen; el conjunto refinado ocupa aproximadamente 2,596 × 6,268 m en ejes del fabricante, pendiente de coordinación entre revisiones.","El acabado de grout HA-35 de 50 mm termina en +0,400; el hormigón termina en +0,350. La losa MAC contigua termina en +0,200.","El cero absoluto de la revisión no está definido; 286,10 m sigue siendo una hipótesis de coordinación.","Se alinea el punto inferior del conjunto del equipo, incluidos los pies ya representados, con la superficie de apoyo terminada; no se añade un espesor de calzos, placa o grout del fabricante no documentado."] | {"revision":"Detalle en planta de 2026-04-30 coordinado de forma preliminar con envolventes y alturas de 2026-08-25","status":"provisional","verticalRule":"Altura total documentada: 3,38 m. Plataforma gráfica de 0,15 m; los cuerpos extraídos de la planta reciben alturas provisionales entre 1,00 y 3,38 m, detalladas por subvolumen. No se dispone de alzado acotado de cada componente.","partCount":26,"source":{"documentId":"EQ-IMPLANTACION-20260430","title":"Plano del fabricante: implantación de equipos","sheet":"LHD2609-GD01000 · espacio modelo","date":"2026-04-30"},"heightSource":{"documentId":"EQ-CARGAS-20260825","title":"Plano del fabricante: cargas de equipos","sheet":"Espacio modelo","date":"2026-08-25"},"unconfirmedDimensions":["Todas las alturas parciales son hipótesis de visualización; solo la altura total de 3,38 m está acotada.","Las regiones del dibujo se usan como envolventes de cuerpos; la identificación funcional y la cota Z de cada pieza requieren verificación.","Pequeños taladros, tornillería y detalles interiores de las regiones no se extruyen como vacíos de fabricación."],"quantityUse":"Magnitudes de la geometría representada; no son cantidades de material, obra, compra, capacidad útil ni fabricación. En geometrías compuestas se suman superficies y volúmenes de partes y pueden existir solapes no depurados.","partsAreBOM":false} | equipment_component | {"min":[54.480044,69.250118,1.5],"max":[57.657628,75.654646,4.88]} | {"boundingBoxM":{"min":[54.480044,69.250118,1.5],"max":[57.657628,75.654646,4.88]},"extentsM":[3.177584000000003,6.404527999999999,3.38],"meshSurfaceM2":165.19823454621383,"meshVolumeM3":20.17010370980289,"closedSolid":true,"windingConsistent":true,"basis":"Submalla exacta de los triángulos del modelo IFC coordinado; separación de componentes sin transformación ni retesselación."} | ["Todas las alturas parciales son hipótesis de visualización; solo la altura total de 3,38 m está acotada.","Las regiones del dibujo se usan como envolventes de cuerpos; la identificación funcional y la cota Z de cada pieza requieren verificación.","Pequeños taladros, tornillería y detalles interiores de las regiones no se extruyen como vacíos de fabricación.","La separación gráfica no aporta cotas de fabricación ni identifica piezas internas no documentadas.","Los materiales y acabados permanecen provisionales; las fotografías públicas solo orientan la apariencia."] | {"id":"AC1001B--cad-region-024","sourcePartId":"AC1001B--cad-region-024","name":"Cuerpo de equipo · región CAD 24","role":"equipment_component","classificationStatus":"provisional","classificationBasis":"Rol del subvolumen gráfico según el activo de detalle; identidad de fabricación no confirmada.","parentEquipmentId":"AC1001B","parentEquipmentGuid":"1IHLxwSiXVEvsMWIfO71jb","isAssemblyIdentityCarrier":false,"sourceFaceRange":[1536,1556],"sourceCurrentFaceIndices":[1536,1537,1538,1539,1540,1541,1542,1543,1544,1545,1546,1547,1548,1549,1550,1551,1552,1553,1554,1555],"sourceMeshSha256":"7b60c904c9d84d22fded9be34af09a09a9c198ec8e75e61902634d5e4064c761","sourceVertexIndices":[806,807,808,809,810,811,812,813,814,815,816,817],"separationMethod":"Partición exacta de triángulos existentes; coordenadas y orientación de caras conservadas.","quantityUse":"Magnitudes geométricas del subvolumen; no son cantidades netas de material, fabricación, suministro o capacidad."} | {"id":"AC1001B","name":"Compresor de aire AC1001B","relationship":"decomposed_component","parentShapeMeaning":"La forma del objeto que conserva el ID del equipo es únicamente su componente principal; el conjunto completo requiere sus hijos."} | {"kind":"through_parent","parentEquipmentId":"AC1001B","directAnchorageVerified":false,"note":"La relación del conjunto con cimentaciones se conserva en el objeto que mantiene el ID del equipo; no se atribuye fijación directa a cada subcomponente."} | Documento de implantación y apoyo del conjunto padre; no acredita fijación individual de este componente. | AC1001B--cad-region-024 | Cuerpo de equipo · región CAD 24 | Equipos | unknown | equipment_light_gray | {"documentId":"EQ-IMPLANTACION-20260430","title":"Plano del fabricante: implantación de equipos","sheet":"LHD2609-GD01000 · espacio modelo","date":"2026-04-30","componentSourceHandles":["7134F","71355","71DB1","72F08","72F0B","72F10","72F11"]} | Submalla de triángulos existentes; no hay nueva posición ni nuevas caras. | Cotas globales del conjunto conservadas aparte; las dimensiones de esta ficha son de la submalla. | Coordinación del conjunto padre; anclaje directo individual no acreditado. | Superficie y volumen geométricos brutos; no constituyen cantidades netas de obra, material o fabricación. | Plano general y dimensiones globales de AC1001B; no se asignan esas dimensiones globales a este componente. | ["7134F","71355","71DB1","72F08","72F0B","72F10","72F11"] | 1 | no | Submalla exacta; interpretación funcional y cotas parciales provisionales.
Compresor de aire AC1001B · Cuerpo de equipo · región CAD 25 | Componente de equipo · cuerpo o accesorio | Plano del fabricante: implantación de equipos · referencia E7 | 0.339518 | 0.339518 | 2.1 | 286.65 | 288.75 | 2.41939 | 0.189473 | Apoyo relativo +0.400 m; cero absoluto provisional | Componente de equipo · cuerpo o accesorio | equipmentComponent | {"name":"No especificado","source":"Sin especificación de material en la documentación revisada","status":"unknown"} | {"documented":[{"label":"Referencia dimensional del conjunto","value":"Plano general y dimensiones globales de AC1001B; no se asignan esas dimensiones globales a este componente.","unit":"","source":"EQ-IMPLANTACION-20260430 · LHD2609-GD01000 · espacio modelo","status":"referencia_del_conjunto"}],"geometry":[{"label":"Extensión de la malla en X","value":0.3395179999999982,"unit":"m","source":"Geometría releída del IFC; datum absoluto de proceso provisional","status":"derivado"},{"label":"Extensión de la malla en Y","value":0.3395180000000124,"unit":"m","source":"Geometría releída del IFC; datum absoluto de proceso provisional","status":"derivado"},{"label":"Extensión de la malla en Z","value":2.1,"unit":"m","source":"Geometría releída del IFC; datum absoluto de proceso provisional","status":"derivado"},{"label":"Cota inferior de visualización","value":286.65,"unit":"m","source":"Geometría releída del IFC; datum absoluto de proceso provisional","status":"derivado"},{"label":"Cota superior de visualización","value":288.75,"unit":"m","source":"Geometría releída del IFC; datum absoluto de proceso provisional","status":"derivado"}],"notes":["Las dimensiones del equipo completo se conservan en parentEquipmentDimensions.","Las extensiones en X/Y son de los ejes del modelo y no sustituyen cotas locales de fabricación.","No se infieren espesores de chapa, tolerancias ni dimensiones de piezas a partir de la partición."]} | {"documentId":"EQ-IMPLANTACION-20260430","title":"Plano del fabricante: implantación de equipos","sheet":"LHD2609-GD01000 · espacio modelo","date":"2026-04-30","componentSourceHandles":["71621","71642","7164D","71969","7196A","7196F","71974","71976","73116","73117","73118","73119","7311A","7311B","7311C","7311D","7311E","7311F","73120","73121","73122","73124","73125","73128","7312E","73138","73139","73181","73183","73186","7318B","73195","73197","73199","7319A","731A1","731A7","7340D","7340F","73419","7341B","73420","73422","7342C","7342E"]} | {"horizontalStatus":"derivado_del_conjunto","verticalStatus":"derivado_del_conjunto","coordinateSystem":"model_local_m","parentEquipmentId":"AC1001B","transformApplied":false,"note":"Coordenadas copiadas exactamente del equipo coordinado; no se ha movido, girado, elevado ni reescalado este componente.","foundationRelationship":"El apoyo y las cotas de instalación se documentan para el conjunto padre. Esta submalla no acredita un anclaje directo.","meshMinimumAbsoluteElevationM":286.65,"assemblyPlacementField":"parentEquipmentPositioning"} | ["Componente separado de una reconstrucción documental del conjunto. Las alturas y detalles parciales conservan las limitaciones del fabricante registradas en parentEquipmentIssues.","Esta representación exterior no crea una chapa hueca ni añade componentes internos no documentados.","La pertenencia al conjunto no demuestra apoyo o anclaje directo a la cimentación."] | {"source":{"documentId":"EQ-IMPLANTACION-20260430","title":"Plano del fabricante: implantación de equipos","sheet":"LHD2609-GD01000 · espacio modelo","date":"2026-04-30","componentSourceHandles":["71621","71642","7164D","71969","7196A","7196F","71974","71976","73116","73117","73118","73119","7311A","7311B","7311C","7311D","7311E","7311F","73120","73121","73122","73124","73125","73128","7312E","73138","73139","73181","73183","73186","7318B","73195","73197","73199","7319A","731A1","731A7","7340D","7340F","73419","7341B","73420","73422","7342C","7342E"]},"sourcePartId":"AC1001B--cad-region-025","sourceHandles":["71621","71642","7164D","71969","7196A","7196F","71974","71976","73116","73117","73118","73119","7311A","7311B","7311C","7311D","7311E","7311F","73120","73121","73122","73124","73125","73128","7312E","73138","73139","73181","73183","73186","7318B","73195","73197","73199","7319A","731A1","731A7","7340D","7340F","73419","7341B","73420","73422","7342C","7342E"],"partCount":1,"partsAreBOM":false,"status":"Submalla exacta; interpretación funcional y cotas parciales provisionales."} | {"boundingBoxM":{"min":[56.434069,72.499096,1.65],"max":[56.773587,72.838614,3.75]},"extentsM":[0.339518,0.339518,2.1],"meshSurfaceM2":2.419385,"meshVolumeM3":0.189473,"closedSolid":true,"basis":"Geometría de coordinación. Los volúmenes de referencia y subcomponentes no son cantidades de material ni componentes de fabricación certificados."} | {"documentId":"LHD2609-JG00100-20260904","title":"Cimentaciones y pedestales de equipos · revisión recibida 04/09/2026","date":"2026-09-04","sheet":"1 / 1-1","sourceHandles":["28C35","28C38","28C3B","28C89"]} | equipment | {"id":"equipment","name":"Equipos"} | {"profileId":"equipment_light_gray","name":"Equipo · gris claro provisional","materialName":"No especificado","physicalMaterialStatus":"unknown","physicalMaterialSource":"Sin especificación de material en la documentación revisada","appearanceStatus":"provisional","appearanceBasis":"Referencia visual de fotografías públicas de Jinhong Gas / fabricante. Apariencia provisional para coordinación; fotografías oficiales pueden orientar el color, pero no acreditan el material, el acabado ni el equipo concreto.","appearanceReferences":["jinhong-official-asu"],"note":"El perfil visual no confirma material, grado ni acabado del componente."} | {"status":"componente_independiente","note":"Objeto independiente seleccionable. Las caras se asignan una sola vez entre todos los componentes del conjunto.","parentEquipmentId":"AC1001B","isAssemblyIdentityCarrier":false} | {"elementId":"AC1001B--cad-region-025","ifcGuid":"0E5Kpc61vMixx$5JaXbppz","ifcClass":"IfcBuildingElementProxy","buildingId":"process_plant","buildingName":"Planta de proceso","sourceDocumentId":"EQ-IMPLANTACION-20260430","sourceRepresentationKind":"equipmentComponent"} | {"layerId":"equipment","layerName":"Equipos","role":"Componente de equipo · cuerpo o accesorio","basis":"Clasificación por función del elemento; no modifica las especificaciones documentales."} | {"profileId":"equipment_light_gray","name":"Equipo · gris claro provisional","status":"provisional","basis":"Referencia visual de fotografías públicas de Jinhong Gas / fabricante. Apariencia provisional para coordinación; fotografías oficiales pueden orientar el color, pero no acreditan el material, el acabado ni el equipo concreto.","physicalMaterialUnchanged":true} | Equipos | No especificado | Equipos | Equipo · gris claro provisional | provisional | AC1001B--cad-region-025 | ["Componente separado de una reconstrucción documental del conjunto. Las alturas y detalles parciales conservan las limitaciones del fabricante registradas en parentEquipmentIssues.","Esta representación exterior no crea una chapa hueca ni añade componentes internos no documentados.","La pertenencia al conjunto no demuestra apoyo o anclaje directo a la cimentación."] | Geometría de coordinación. Los volúmenes de referencia y subcomponentes no son cantidades de material ni componentes de fabricación certificados. | Sin especificación de material en la documentación revisada | {"documentId":"EQ-IMPLANTACION-20260430","title":"Plano del fabricante: implantación de equipos","sheet":"LHD2609-GD01000 · espacio modelo","date":"2026-04-30","componentSourceHandles":["71621","71642","7164D","71969","7196A","7196F","71974","71976","73116","73117","73118","73119","7311A","7311B","7311C","7311D","7311E","7311F","73120","73121","73122","73124","73125","73128","7312E","73138","73139","73181","73183","73186","7318B","73195","73197","73199","7319A","731A1","731A7","7340D","7340F","73419","7341B","73420","73422","7342C","7342E"]} | yes | equipment_light_gray | [0.88,0.89,0.88] | 0.45 | 0.28 | Referencia visual de fotografías públicas de Jinhong Gas / fabricante. Apariencia provisional para coordinación; fotografías oficiales pueden orientar el color, pero no acreditan el material, el acabado ni el equipo concreto. | La apariencia no certifica el material físico ni el acabado de fabricación. | BIM · Equipos | AC1001B | Compresor de aire AC1001B | IfcCompressor | {"documented":[{"label":"Dimensión X local del bastidor de referencia CAD","value":2.35,"unit":"m","source":"EQ-CARGAS-20260825 · contorno CAD · handles 3ED","status":"derivado"},{"label":"Dimensión Y local del bastidor de referencia CAD","value":5.22,"unit":"m","source":"EQ-CARGAS-20260825 · contorno CAD · handles 3ED","status":"derivado"},{"label":"Altura acotada","value":3.38,"unit":"m","source":"EQ-CARGAS-20260825 · handle 25A3","status":"documentado"},{"label":"Cota relativa de la superficie de apoyo","value":0.4,"unit":"m","source":"LHD2609-JG00100-20260904 · sección 1 / 1-1 · 28C35, 28C38, 28C3B, 28C89","status":"documentado"}],"geometry":[{"label":"Extensión de la malla en X","value":3.177584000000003,"unit":"m","source":"Geometría releída del IFC; datum absoluto de proceso provisional","status":"derivado"},{"label":"Extensión de la malla en Y","value":6.404527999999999,"unit":"m","source":"Geometría releída del IFC; datum absoluto de proceso provisional","status":"derivado"},{"label":"Extensión de la malla en Z","value":3.3800000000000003,"unit":"m","source":"Geometría releída del IFC; datum absoluto de proceso provisional","status":"derivado"},{"label":"Cota inferior de visualización","value":286.5,"unit":"m","source":"Geometría releída del IFC; datum absoluto de proceso provisional","status":"derivado"},{"label":"Cota superior de visualización","value":289.88,"unit":"m","source":"Geometría releída del IFC; datum absoluto de proceso provisional","status":"derivado"}],"notes":["Las extensiones de la malla se miden en los ejes del proyecto tras el giro de implantación; no sustituyen las dimensiones locales del fabricante.","La envolvente, su volumen y los espesores de visualización no son volúmenes de material ni cantidades de compra, construcción o fabricación.","Las dimensiones documentadas distinguen cotas explícitas y medidas extraídas de contornos CAD; las dimensiones geométricas describen únicamente la malla publicada.","Las extensiones de la malla refinada y las dimensiones documentadas del contorno o bastidor tienen distinto alcance; las cotas parciales del detalle son provisionales."]} | {"Estado de la planta":"Derivado del CAD y del giro de implantación","Nivel relativo del apoyo (m)":0.4,"Estado del nivel relativo":"Documentado en el plano de cimentaciones","Cero absoluto de visualización (m)":286.1,"Estado del cero absoluto":"Provisional","Cota del apoyo de visualización (m)":286.5,"Desplazamiento aplicado a la malla (m)":0.40000000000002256,"Criterio":"Nivel de apoyo relativo documentado. Se adopta el cero de proceso a 286,10 m solo para visualización; la equivalencia absoluta no está confirmada. No se añade un espesor de montaje sin cota del fabricante."} | ["La máquina está contenida en la envolvente de la cabina acústica; su superposición no acredita una interferencia física.","El bastidor CAD coincide con la referencia de 2,35 × 5,22 m del plano de cargas, pero cuerpos y auxiliares del detalle de abril sobresalen de esa referencia, hasta aproximadamente 1,048 m por el extremo sur y 0,246 m por el lado oeste. Extensión geométrica resultante: 2,595899 × 6,268101 × 3,38 m, derivada y pendiente de coordinación entre revisiones. Permanecen dentro de la cabina acústica. Compatibilidad de revisión pendiente de fabricante.","Todas las alturas parciales son hipótesis de visualización; solo la altura total de 3,38 m está acotada.","Las regiones del dibujo se usan como envolventes de cuerpos; la identificación funcional y la cota Z de cada pieza requieren verificación.","Pequeños taladros, tornillería y detalles interiores de las regiones no se extruyen como vacíos de fabricación.","El bastidor documentado mide 2,35 × 5,22 m. Los accesorios del detalle de abril sobresalen; el conjunto refinado ocupa aproximadamente 2,596 × 6,268 m en ejes del fabricante, pendiente de coordinación entre revisiones.","El acabado de grout HA-35 de 50 mm termina en +0,400; el hormigón termina en +0,350. La losa MAC contigua termina en +0,200.","El cero absoluto de la revisión no está definido; 286,10 m sigue siendo una hipótesis de coordinación.","Se alinea el punto inferior del conjunto del equipo, incluidos los pies ya representados, con la superficie de apoyo terminada; no se añade un espesor de calzos, placa o grout del fabricante no documentado."] | {"revision":"Detalle en planta de 2026-04-30 coordinado de forma preliminar con envolventes y alturas de 2026-08-25","status":"provisional","verticalRule":"Altura total documentada: 3,38 m. Plataforma gráfica de 0,15 m; los cuerpos extraídos de la planta reciben alturas provisionales entre 1,00 y 3,38 m, detalladas por subvolumen. No se dispone de alzado acotado de cada componente.","partCount":26,"source":{"documentId":"EQ-IMPLANTACION-20260430","title":"Plano del fabricante: implantación de equipos","sheet":"LHD2609-GD01000 · espacio modelo","date":"2026-04-30"},"heightSource":{"documentId":"EQ-CARGAS-20260825","title":"Plano del fabricante: cargas de equipos","sheet":"Espacio modelo","date":"2026-08-25"},"unconfirmedDimensions":["Todas las alturas parciales son hipótesis de visualización; solo la altura total de 3,38 m está acotada.","Las regiones del dibujo se usan como envolventes de cuerpos; la identificación funcional y la cota Z de cada pieza requieren verificación.","Pequeños taladros, tornillería y detalles interiores de las regiones no se extruyen como vacíos de fabricación."],"quantityUse":"Magnitudes de la geometría representada; no son cantidades de material, obra, compra, capacidad útil ni fabricación. En geometrías compuestas se suman superficies y volúmenes de partes y pueden existir solapes no depurados.","partsAreBOM":false} | equipment_component | {"min":[54.480044,69.250118,1.5],"max":[57.657628,75.654646,4.88]} | {"boundingBoxM":{"min":[54.480044,69.250118,1.5],"max":[57.657628,75.654646,4.88]},"extentsM":[3.177584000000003,6.404527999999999,3.38],"meshSurfaceM2":165.19823454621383,"meshVolumeM3":20.17010370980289,"closedSolid":true,"windingConsistent":true,"basis":"Submalla exacta de los triángulos del modelo IFC coordinado; separación de componentes sin transformación ni retesselación."} | ["Todas las alturas parciales son hipótesis de visualización; solo la altura total de 3,38 m está acotada.","Las regiones del dibujo se usan como envolventes de cuerpos; la identificación funcional y la cota Z de cada pieza requieren verificación.","Pequeños taladros, tornillería y detalles interiores de las regiones no se extruyen como vacíos de fabricación.","La separación gráfica no aporta cotas de fabricación ni identifica piezas internas no documentadas.","Los materiales y acabados permanecen provisionales; las fotografías públicas solo orientan la apariencia."] | {"id":"AC1001B--cad-region-025","sourcePartId":"AC1001B--cad-region-025","name":"Cuerpo de equipo · región CAD 25","role":"equipment_component","classificationStatus":"provisional","classificationBasis":"Rol del subvolumen gráfico según el activo de detalle; identidad de fabricación no confirmada.","parentEquipmentId":"AC1001B","parentEquipmentGuid":"1IHLxwSiXVEvsMWIfO71jb","isAssemblyIdentityCarrier":false,"sourceFaceRange":[1556,1696],"sourceCurrentFaceIndices":[1556,1557,1558,1559,1560,1561,1562,1563,1564,1565,1566,1567,1568,1569,1570,1571,1572,1573,1574,1575,1576,1577,1578,1579,1580,1581,1582,1583,1584,1585,1586,1587,1588,1589,1590,1591,1592,1593,1594,1595,1596,1597,1598,1599,1600,1601,1602,1603,1604,1605,1606,1607,1608,1609,1610,1611,1612,1613,1614,1615,1616,1617,1618,1619,1620,1621,1622,1623,1624,1625,1626,1627,1628,1629,1630,1631,1632,1633,1634,1635,1636,1637,1638,1639,1640,1641,1642,1643,1644,1645,1646,1647,1648,1649,1650,1651,1652,1653,1654,1655,1656,1657,1658,1659,1660,1661,1662,1663,1664,1665,1666,1667,1668,1669,1670,1671,1672,1673,1674,1675,1676,1677,1678,1679,1680,1681,1682,1683,1684,1685,1686,1687,1688,1689,1690,1691,1692,1693,1694,1695],"sourceMeshSha256":"7b60c904c9d84d22fded9be34af09a09a9c198ec8e75e61902634d5e4064c761","sourceVertexIndices":[818,819,820,821,822,823,824,825,826,827,828,829,830,831,832,833,834,835,836,837,838,839,840,841,842,843,844,845,846,847,848,849,850,851,852,853,854,855,856,857,858,859,860,861,862,863,864,865,866,867,868,869,870,871,872,873,874,875,876,877,878,879,880,881,882,883,884,885,886,887,888,889],"separationMethod":"Partición exacta de triángulos existentes; coordenadas y orientación de caras conservadas.","quantityUse":"Magnitudes geométricas del subvolumen; no son cantidades netas de material, fabricación, suministro o capacidad."} | {"id":"AC1001B","name":"Compresor de aire AC1001B","relationship":"decomposed_component","parentShapeMeaning":"La forma del objeto que conserva el ID del equipo es únicamente su componente principal; el conjunto completo requiere sus hijos."} | {"kind":"through_parent","parentEquipmentId":"AC1001B","directAnchorageVerified":false,"note":"La relación del conjunto con cimentaciones se conserva en el objeto que mantiene el ID del equipo; no se atribuye fijación directa a cada subcomponente."} | Documento de implantación y apoyo del conjunto padre; no acredita fijación individual de este componente. | AC1001B--cad-region-025 | Cuerpo de equipo · región CAD 25 | Equipos | unknown | equipment_light_gray | {"documentId":"EQ-IMPLANTACION-20260430","title":"Plano del fabricante: implantación de equipos","sheet":"LHD2609-GD01000 · espacio modelo","date":"2026-04-30","componentSourceHandles":["71621","71642","7164D","71969","7196A","7196F","71974","71976","73116","73117","73118","73119","7311A","7311B","7311C","7311D","7311E","7311F","73120","73121","73122","73124","73125","73128","7312E","73138","73139","73181","73183","73186","7318B","73195","73197","73199","7319A","731A1","731A7","7340D","7340F","73419","7341B","73420","73422","7342C","7342E"]} | Submalla de triángulos existentes; no hay nueva posición ni nuevas caras. | Cotas globales del conjunto conservadas aparte; las dimensiones de esta ficha son de la submalla. | Coordinación del conjunto padre; anclaje directo individual no acreditado. | Superficie y volumen geométricos brutos; no constituyen cantidades netas de obra, material o fabricación. | Plano general y dimensiones globales de AC1001B; no se asignan esas dimensiones globales a este componente. | ["71621","71642","7164D","71969","7196A","7196F","71974","71976","73116","73117","73118","73119","7311A","7311B","7311C","7311D","7311E","7311F","73120","73121","73122","73124","73125","73128","7312E","73138","73139","73181","73183","73186","7318B","73195","73197","73199","7319A","731A1","731A7","7340D","7340F","73419","7341B","73420","73422","7342C","7342E"] | 1 | no | Submalla exacta; interpretación funcional y cotas parciales provisionales.
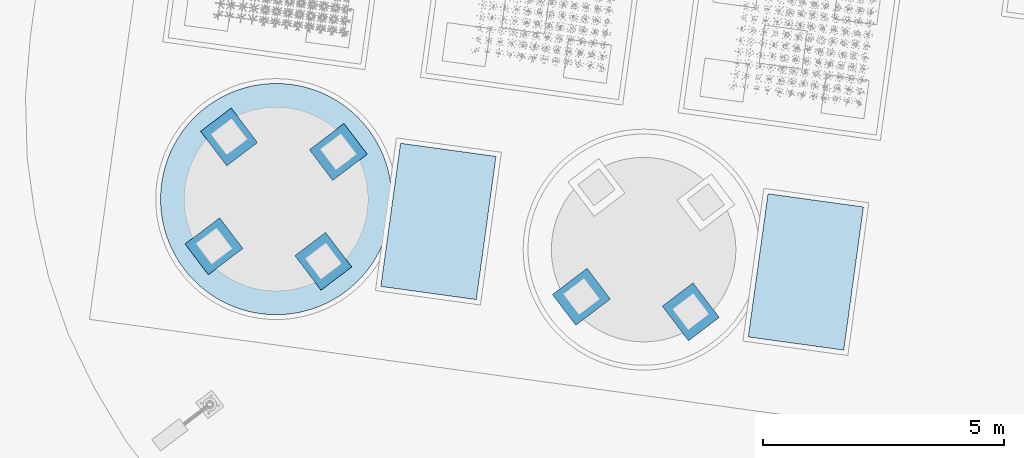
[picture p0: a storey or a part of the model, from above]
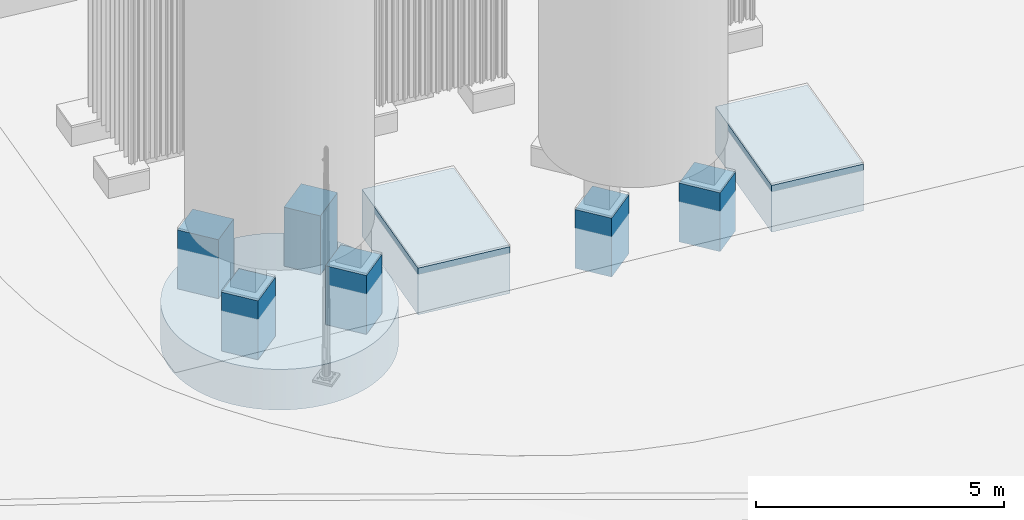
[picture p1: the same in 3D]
Properties of the parts of a building model (IFC4), part 43 of 134

# IfcBuildingElementProxy (140)
Name | Description | Document | Extensión de la malla en X (m) = ExtensionX (m) | Extensión de la malla en Y (m) = ExtensionY (m) | Extensión de la malla en Z (m) = ExtensionZ (m) | Cota inferior de visualización (m) | Cota superior de visualización (m) | SuperficieDeLaMalla (m2) | VolumenGeometrico (m3) | level | category = Categoria = Funcion | representationKind | material | dimensions | JH_InformacionBIM, source = DocumentoFuente | positioning = PosicionYEstado | issues | detailGeometry | geometryMetrics | installationSource | layerId = IdentificadorCapa | visualLayer | materialAppearance | componentSeparation | visualizationIdentity | classification | appearance | Disciplina | Material | Capa BIM = NombreCapa | Acabado de visualización = Acabado | Estado del acabado = Estado | Identificador | JH_Trazabilidad, IncidenciasPendientes | UsoDeLasMagnitudes | JH_EvidenciaDeMaterial, source | JH_DetalleGeometrico, source | VisibilidadInicial | Perfil | ColorRGB | Rugosidad | Metallicidad | Referencia | Nota | Group | parentEquipmentId = Identificador del equipo padre | parentEquipmentName = Equipo padre | parentEquipmentIfcClass | parentEquipmentDimensions | parentEquipmentPositioning | parentEquipmentIssues | parentEquipmentDetail | componentRole = Rol del componente | assemblyBBox | assemblyGeometryMetrics | manufacturerDetailsPending | component | assembly | foundationRelationship | installationSourceScope | Identificador del elemento = sourcePartId | Componente | Capa de visualización | Estado del material | Perfil visual del material | Fuente del componente | Criterio de partición | Criterio de las dimensiones | Relación con cimentaciones | Aplicabilidad de las mediciones | Referencia dimensional del conjunto | sourceHandles | partCount | partsAreBOM | status
Compresor de aire AC1001C · Carcasa principal · región CAD 4 | Componente de equipo · envolvente exterior | Plano del fabricante: implantación de equipos · referencia E7 | 1.41027 | 0.611248 | 2.3 | 286.65 | 288.95 | 9.43335 | 1.35843 | Apoyo relativo +0.400 m; cero absoluto provisional | Componente de equipo · envolvente exterior | equipmentComponent | {"name":"No especificado","source":"Sin especificación de material en la documentación revisada","status":"unknown"} | {"documented":[{"label":"Referencia dimensional del conjunto","value":"Plano general y dimensiones globales de AC1001C; no se asignan esas dimensiones globales a este componente.","unit":"","source":"EQ-IMPLANTACION-20260430 · LHD2609-GD01000 · espacio modelo","status":"referencia_del_conjunto"}],"geometry":[{"label":"Extensión de la malla en X","value":1.410269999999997,"unit":"m","source":"Geometría releída del IFC; datum absoluto de proceso provisional","status":"derivado"},{"label":"Extensión de la malla en Y","value":0.6112480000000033,"unit":"m","source":"Geometría releída del IFC; datum absoluto de proceso provisional","status":"derivado"},{"label":"Extensión de la malla en Z","value":2.3000000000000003,"unit":"m","source":"Geometría releída del IFC; datum absoluto de proceso provisional","status":"derivado"},{"label":"Cota inferior de visualización","value":286.65,"unit":"m","source":"Geometría releída del IFC; datum absoluto de proceso provisional","status":"derivado"},{"label":"Cota superior de visualización","value":288.95,"unit":"m","source":"Geometría releída del IFC; datum absoluto de proceso provisional","status":"derivado"}],"notes":["Las dimensiones del equipo completo se conservan en parentEquipmentDimensions.","Las extensiones en X/Y son de los ejes del modelo y no sustituyen cotas locales de fabricación.","No se infieren espesores de chapa, tolerancias ni dimensiones de piezas a partir de la partición."]} | {"documentId":"EQ-IMPLANTACION-20260430","title":"Plano del fabricante: implantación de equipos","sheet":"LHD2609-GD01000 · espacio modelo","date":"2026-04-30","componentSourceHandles":["73405","73406","73407"]} | {"horizontalStatus":"derivado_del_conjunto","verticalStatus":"derivado_del_conjunto","coordinateSystem":"model_local_m","parentEquipmentId":"AC1001C","transformApplied":false,"note":"Coordenadas copiadas exactamente del equipo coordinado; no se ha movido, girado, elevado ni reescalado este componente.","foundationRelationship":"El apoyo y las cotas de instalación se documentan para el conjunto padre. Esta submalla no acredita un anclaje directo.","meshMinimumAbsoluteElevationM":286.65,"assemblyPlacementField":"parentEquipmentPositioning"} | ["Componente separado de una reconstrucción documental del conjunto. Las alturas y detalles parciales conservan las limitaciones del fabricante registradas en parentEquipmentIssues.","Esta representación exterior no crea una chapa hueca ni añade componentes internos no documentados.","La pertenencia al conjunto no demuestra apoyo o anclaje directo a la cimentación."] | {"source":{"documentId":"EQ-IMPLANTACION-20260430","title":"Plano del fabricante: implantación de equipos","sheet":"LHD2609-GD01000 · espacio modelo","date":"2026-04-30","componentSourceHandles":["73405","73406","73407"]},"sourcePartId":"AC1001C--cad-region-004","sourceHandles":["73405","73406","73407"],"partCount":1,"partsAreBOM":false,"status":"Submalla exacta; interpretación funcional y cotas parciales provisionales."} | {"boundingBoxM":{"min":[61.179555,68.86112,1.65],"max":[62.589825,69.472368,3.95]},"extentsM":[1.41027,0.611248,2.3],"meshSurfaceM2":9.433346,"meshVolumeM3":1.358434,"closedSolid":true,"basis":"Geometría de coordinación. Los volúmenes de referencia y subcomponentes no son cantidades de material ni componentes de fabricación certificados."} | {"documentId":"LHD2609-JG00100-20260904","title":"Cimentaciones y pedestales de equipos · revisión recibida 04/09/2026","date":"2026-09-04","sheet":"1 / 1-1","sourceHandles":["28C35","28C38","28C3B","28C89"]} | equipment_enclosures | {"id":"equipment_enclosures","name":"Envolventes de equipos"} | {"profileId":"equipment_light_gray","name":"Equipo · gris claro provisional","materialName":"No especificado","physicalMaterialStatus":"unknown","physicalMaterialSource":"Sin especificación de material en la documentación revisada","appearanceStatus":"provisional","appearanceBasis":"Referencia visual de fotografías públicas de Jinhong Gas / fabricante. Apariencia provisional para coordinación; fotografías oficiales pueden orientar el color, pero no acreditan el material, el acabado ni el equipo concreto.","appearanceReferences":["jinhong-official-asu"],"note":"El perfil visual no confirma material, grado ni acabado del componente."} | {"status":"componente_independiente","note":"Objeto independiente seleccionable. Las caras se asignan una sola vez entre todos los componentes del conjunto.","parentEquipmentId":"AC1001C","isAssemblyIdentityCarrier":false} | {"elementId":"AC1001C--cad-region-004","ifcGuid":"2L36OM4w1OTuLifERBt8LK","ifcClass":"IfcBuildingElementProxy","buildingId":"process_plant","buildingName":"Planta de proceso","sourceDocumentId":"EQ-IMPLANTACION-20260430","sourceRepresentationKind":"equipmentComponent"} | {"layerId":"equipment_enclosures","layerName":"Envolventes de equipos","role":"Componente de equipo · envolvente exterior","basis":"Clasificación por función del elemento; no modifica las especificaciones documentales."} | {"profileId":"equipment_light_gray","name":"Equipo · gris claro provisional","status":"provisional","basis":"Referencia visual de fotografías públicas de Jinhong Gas / fabricante. Apariencia provisional para coordinación; fotografías oficiales pueden orientar el color, pero no acreditan el material, el acabado ni el equipo concreto.","physicalMaterialUnchanged":true} | Envolventes de equipos | No especificado | Envolventes de equipos | Equipo · gris claro provisional | provisional | AC1001C--cad-region-004 | ["Componente separado de una reconstrucción documental del conjunto. Las alturas y detalles parciales conservan las limitaciones del fabricante registradas en parentEquipmentIssues.","Esta representación exterior no crea una chapa hueca ni añade componentes internos no documentados.","La pertenencia al conjunto no demuestra apoyo o anclaje directo a la cimentación."] | Geometría de coordinación. Los volúmenes de referencia y subcomponentes no son cantidades de material ni componentes de fabricación certificados. | Sin especificación de material en la documentación revisada | {"documentId":"EQ-IMPLANTACION-20260430","title":"Plano del fabricante: implantación de equipos","sheet":"LHD2609-GD01000 · espacio modelo","date":"2026-04-30","componentSourceHandles":["73405","73406","73407"]} | yes | equipment_light_gray | [0.88,0.89,0.88] | 0.45 | 0.28 | Referencia visual de fotografías públicas de Jinhong Gas / fabricante. Apariencia provisional para coordinación; fotografías oficiales pueden orientar el color, pero no acreditan el material, el acabado ni el equipo concreto. | La apariencia no certifica el material físico ni el acabado de fabricación. | BIM · Envolventes de equipos | AC1001C | Compresor de aire AC1001C | IfcCompressor | {"documented":[{"label":"Dimensión X local del bastidor de referencia CAD","value":2.35,"unit":"m","source":"EQ-CARGAS-20260825 · contorno CAD · handles 3F0","status":"derivado"},{"label":"Dimensión Y local del bastidor de referencia CAD","value":5.22,"unit":"m","source":"EQ-CARGAS-20260825 · contorno CAD · handles 3F0","status":"derivado"},{"label":"Altura acotada","value":3.38,"unit":"m","source":"EQ-CARGAS-20260825 · handle 25AF","status":"documentado"},{"label":"Cota relativa de la superficie de apoyo","value":0.4,"unit":"m","source":"LHD2609-JG00100-20260904 · sección 1 / 1-1 · 28C35, 28C38, 28C3B, 28C89","status":"documentado"}],"geometry":[{"label":"Extensión de la malla en X","value":3.177584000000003,"unit":"m","source":"Geometría releída del IFC; datum absoluto de proceso provisional","status":"derivado"},{"label":"Extensión de la malla en Y","value":6.404527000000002,"unit":"m","source":"Geometría releída del IFC; datum absoluto de proceso provisional","status":"derivado"},{"label":"Extensión de la malla en Z","value":3.3800000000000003,"unit":"m","source":"Geometría releída del IFC; datum absoluto de proceso provisional","status":"derivado"},{"label":"Cota inferior de visualización","value":286.5,"unit":"m","source":"Geometría releída del IFC; datum absoluto de proceso provisional","status":"derivado"},{"label":"Cota superior de visualización","value":289.88,"unit":"m","source":"Geometría releída del IFC; datum absoluto de proceso provisional","status":"derivado"}],"notes":["Las extensiones de la malla se miden en los ejes del proyecto tras el giro de implantación; no sustituyen las dimensiones locales del fabricante.","La envolvente, su volumen y los espesores de visualización no son volúmenes de material ni cantidades de compra, construcción o fabricación.","Las dimensiones documentadas distinguen cotas explícitas y medidas extraídas de contornos CAD; las dimensiones geométricas describen únicamente la malla publicada.","Las extensiones de la malla refinada y las dimensiones documentadas del contorno o bastidor tienen distinto alcance; las cotas parciales del detalle son provisionales."]} | {"Estado de la planta":"Derivado del CAD y del giro de implantación","Nivel relativo del apoyo (m)":0.4,"Estado del nivel relativo":"Documentado en el plano de cimentaciones","Cero absoluto de visualización (m)":286.1,"Estado del cero absoluto":"Provisional","Cota del apoyo de visualización (m)":286.5,"Desplazamiento aplicado a la malla (m)":0.40000000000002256,"Criterio":"Nivel de apoyo relativo documentado. Se adopta el cero de proceso a 286,10 m solo para visualización; la equivalencia absoluta no está confirmada. No se añade un espesor de montaje sin cota del fabricante."} | ["La máquina está contenida en la envolvente de la cabina acústica; su superposición no acredita una interferencia física.","El bastidor CAD coincide con la referencia de 2,35 × 5,22 m del plano de cargas, pero cuerpos y auxiliares del detalle de abril sobresalen de esa referencia, hasta aproximadamente 1,048 m por el extremo sur y 0,246 m por el lado oeste. Extensión geométrica resultante: 2,595899 × 6,268101 × 3,38 m, derivada y pendiente de coordinación entre revisiones. Permanecen dentro de la cabina acústica. Compatibilidad de revisión pendiente de fabricante.","Todas las alturas parciales son hipótesis de visualización; solo la altura total de 3,38 m está acotada.","Las regiones del dibujo se usan como envolventes de cuerpos; la identificación funcional y la cota Z de cada pieza requieren verificación.","Pequeños taladros, tornillería y detalles interiores de las regiones no se extruyen como vacíos de fabricación.","El bastidor documentado mide 2,35 × 5,22 m. Los accesorios del detalle de abril sobresalen; el conjunto refinado ocupa aproximadamente 2,596 × 6,268 m en ejes del fabricante, pendiente de coordinación entre revisiones.","El acabado de grout HA-35 de 50 mm termina en +0,400; el hormigón termina en +0,350. La losa MAC contigua termina en +0,200.","El cero absoluto de la revisión no está definido; 286,10 m sigue siendo una hipótesis de coordinación.","Se alinea el punto inferior del conjunto del equipo, incluidos los pies ya representados, con la superficie de apoyo terminada; no se añade un espesor de calzos, placa o grout del fabricante no documentado."] | {"revision":"Detalle en planta de 2026-04-30 coordinado de forma preliminar con envolventes y alturas de 2026-08-25","status":"provisional","verticalRule":"Altura total documentada: 3,38 m. Plataforma gráfica de 0,15 m; los cuerpos extraídos de la planta reciben alturas provisionales entre 1,00 y 3,38 m, detalladas por subvolumen. No se dispone de alzado acotado de cada componente.","partCount":26,"source":{"documentId":"EQ-IMPLANTACION-20260430","title":"Plano del fabricante: implantación de equipos","sheet":"LHD2609-GD01000 · espacio modelo","date":"2026-04-30"},"heightSource":{"documentId":"EQ-CARGAS-20260825","title":"Plano del fabricante: cargas de equipos","sheet":"Espacio modelo","date":"2026-08-25"},"unconfirmedDimensions":["Todas las alturas parciales son hipótesis de visualización; solo la altura total de 3,38 m está acotada.","Las regiones del dibujo se usan como envolventes de cuerpos; la identificación funcional y la cota Z de cada pieza requieren verificación.","Pequeños taladros, tornillería y detalles interiores de las regiones no se extruyen como vacíos de fabricación."],"quantityUse":"Magnitudes de la geometría representada; no son cantidades de material, obra, compra, capacidad útil ni fabricación. En geometrías compuestas se suman superficies y volúmenes de partes y pueden existir solapes no depurados.","partsAreBOM":false} | provisional_casing_region | {"min":[60.820401,68.378413,1.5],"max":[63.997985,74.78294,4.88]} | {"boundingBoxM":{"min":[60.820401,68.378413,1.5],"max":[63.997985,74.78294,4.88]},"extentsM":[3.177584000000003,6.404527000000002,3.38],"meshSurfaceM2":165.19823143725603,"meshVolumeM3":20.170106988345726,"closedSolid":true,"windingConsistent":true,"basis":"Submalla exacta de los triángulos del modelo IFC coordinado; separación de componentes sin transformación ni retesselación."} | ["Todas las alturas parciales son hipótesis de visualización; solo la altura total de 3,38 m está acotada.","Las regiones del dibujo se usan como envolventes de cuerpos; la identificación funcional y la cota Z de cada pieza requieren verificación.","Pequeños taladros, tornillería y detalles interiores de las regiones no se extruyen como vacíos de fabricación.","La separación gráfica no aporta cotas de fabricación ni identifica piezas internas no documentadas.","Los materiales y acabados permanecen provisionales; las fotografías públicas solo orientan la apariencia."] | {"id":"AC1001C--cad-region-004","sourcePartId":"AC1001C--cad-region-004","name":"Carcasa principal · región CAD 4","role":"provisional_casing_region","classificationStatus":"provisional","classificationBasis":"Rol del subvolumen gráfico según el activo de detalle; identidad de fabricación no confirmada.","parentEquipmentId":"AC1001C","parentEquipmentGuid":"2IJ0PLLizIvfouRXAkczXf","isAssemblyIdentityCarrier":false,"sourceFaceRange":[124,140],"sourceCurrentFaceIndices":[124,125,126,127,128,129,130,131,132,133,134,135,136,137,138,139],"sourceMeshSha256":"7b60c904c9d84d22fded9be34af09a09a9c198ec8e75e61902634d5e4064c761","sourceVertexIndices":[70,71,72,73,74,75,76,77,78,79],"separationMethod":"Partición exacta de triángulos existentes; coordenadas y orientación de caras conservadas.","quantityUse":"Magnitudes geométricas del subvolumen; no son cantidades netas de material, fabricación, suministro o capacidad."} | {"id":"AC1001C","name":"Compresor de aire AC1001C","relationship":"decomposed_component","parentShapeMeaning":"La forma del objeto que conserva el ID del equipo es únicamente su componente principal; el conjunto completo requiere sus hijos."} | {"kind":"through_parent","parentEquipmentId":"AC1001C","directAnchorageVerified":false,"note":"La relación del conjunto con cimentaciones se conserva en el objeto que mantiene el ID del equipo; no se atribuye fijación directa a cada subcomponente."} | Documento de implantación y apoyo del conjunto padre; no acredita fijación individual de este componente. | AC1001C--cad-region-004 | Carcasa principal · región CAD 4 | Envolventes de equipos | unknown | equipment_light_gray | {"documentId":"EQ-IMPLANTACION-20260430","title":"Plano del fabricante: implantación de equipos","sheet":"LHD2609-GD01000 · espacio modelo","date":"2026-04-30","componentSourceHandles":["73405","73406","73407"]} | Submalla de triángulos existentes; no hay nueva posición ni nuevas caras. | Cotas globales del conjunto conservadas aparte; las dimensiones de esta ficha son de la submalla. | Coordinación del conjunto padre; anclaje directo individual no acreditado. | Superficie y volumen geométricos brutos; no constituyen cantidades netas de obra, material o fabricación. | Plano general y dimensiones globales de AC1001C; no se asignan esas dimensiones globales a este componente. | ["73405","73406","73407"] | 1 | no | Submalla exacta; interpretación funcional y cotas parciales provisionales.
Compresor de aire AC1001C · Cuerpo de equipo · región CAD 5 | Componente de equipo · cuerpo o accesorio | Plano del fabricante: implantación de equipos · referencia E7 | 1.30116 | 0.504363 | 2.1 | 286.65 | 288.75 | 7.08392 | 0.827161 | Apoyo relativo +0.400 m; cero absoluto provisional | Componente de equipo · cuerpo o accesorio | equipmentComponent | {"name":"No especificado","source":"Sin especificación de material en la documentación revisada","status":"unknown"} | {"documented":[{"label":"Referencia dimensional del conjunto","value":"Plano general y dimensiones globales de AC1001C; no se asignan esas dimensiones globales a este componente.","unit":"","source":"EQ-IMPLANTACION-20260430 · LHD2609-GD01000 · espacio modelo","status":"referencia_del_conjunto"}],"geometry":[{"label":"Extensión de la malla en X","value":1.3011630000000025,"unit":"m","source":"Geometría releída del IFC; datum absoluto de proceso provisional","status":"derivado"},{"label":"Extensión de la malla en Y","value":0.5043629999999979,"unit":"m","source":"Geometría releída del IFC; datum absoluto de proceso provisional","status":"derivado"},{"label":"Extensión de la malla en Z","value":2.1,"unit":"m","source":"Geometría releída del IFC; datum absoluto de proceso provisional","status":"derivado"},{"label":"Cota inferior de visualización","value":286.65,"unit":"m","source":"Geometría releída del IFC; datum absoluto de proceso provisional","status":"derivado"},{"label":"Cota superior de visualización","value":288.75,"unit":"m","source":"Geometría releída del IFC; datum absoluto de proceso provisional","status":"derivado"}],"notes":["Las dimensiones del equipo completo se conservan en parentEquipmentDimensions.","Las extensiones en X/Y son de los ejes del modelo y no sustituyen cotas locales de fabricación.","No se infieren espesores de chapa, tolerancias ni dimensiones de piezas a partir de la partición."]} | {"documentId":"EQ-IMPLANTACION-20260430","title":"Plano del fabricante: implantación de equipos","sheet":"LHD2609-GD01000 · espacio modelo","date":"2026-04-30","componentSourceHandles":["71365","7166E","7167F","71926","71928","721E1","721E4","724C3","724CC","724CE","724D9","72513","7252D","7252E","7252F","72531","729A2","729A3","729A5","729A8","72C01","72C02","7302A","73042","73078","730A8","730FF","73101","73103","73105","73106","73107","73110","73112","73114","73115","732E7","73401","73404","73405","73406","73407"]} | {"horizontalStatus":"derivado_del_conjunto","verticalStatus":"derivado_del_conjunto","coordinateSystem":"model_local_m","parentEquipmentId":"AC1001C","transformApplied":false,"note":"Coordenadas copiadas exactamente del equipo coordinado; no se ha movido, girado, elevado ni reescalado este componente.","foundationRelationship":"El apoyo y las cotas de instalación se documentan para el conjunto padre. Esta submalla no acredita un anclaje directo.","meshMinimumAbsoluteElevationM":286.65,"assemblyPlacementField":"parentEquipmentPositioning"} | ["Componente separado de una reconstrucción documental del conjunto. Las alturas y detalles parciales conservan las limitaciones del fabricante registradas en parentEquipmentIssues.","Esta representación exterior no crea una chapa hueca ni añade componentes internos no documentados.","La pertenencia al conjunto no demuestra apoyo o anclaje directo a la cimentación."] | {"source":{"documentId":"EQ-IMPLANTACION-20260430","title":"Plano del fabricante: implantación de equipos","sheet":"LHD2609-GD01000 · espacio modelo","date":"2026-04-30","componentSourceHandles":["71365","7166E","7167F","71926","71928","721E1","721E4","724C3","724CC","724CE","724D9","72513","7252D","7252E","7252F","72531","729A2","729A3","729A5","729A8","72C01","72C02","7302A","73042","73078","730A8","730FF","73101","73103","73105","73106","73107","73110","73112","73114","73115","732E7","73401","73404","73405","73406","73407"]},"sourcePartId":"AC1001C--cad-region-005","sourceHandles":["71365","7166E","7167F","71926","71928","721E1","721E4","724C3","724CC","724CE","724D9","72513","7252D","7252E","7252F","72531","729A2","729A3","729A5","729A8","72C01","72C02","7302A","73042","73078","730A8","730FF","73101","73103","73105","73106","73107","73110","73112","73114","73115","732E7","73401","73404","73405","73406","73407"],"partCount":1,"partsAreBOM":false,"status":"Submalla exacta; interpretación funcional y cotas parciales provisionales."} | {"boundingBoxM":{"min":[61.557809,71.397454,1.65],"max":[62.858972,71.901817,3.75]},"extentsM":[1.301163,0.504363,2.1],"meshSurfaceM2":7.083915,"meshVolumeM3":0.827161,"closedSolid":true,"basis":"Geometría de coordinación. Los volúmenes de referencia y subcomponentes no son cantidades de material ni componentes de fabricación certificados."} | {"documentId":"LHD2609-JG00100-20260904","title":"Cimentaciones y pedestales de equipos · revisión recibida 04/09/2026","date":"2026-09-04","sheet":"1 / 1-1","sourceHandles":["28C35","28C38","28C3B","28C89"]} | equipment | {"id":"equipment","name":"Equipos"} | {"profileId":"equipment_light_gray","name":"Equipo · gris claro provisional","materialName":"No especificado","physicalMaterialStatus":"unknown","physicalMaterialSource":"Sin especificación de material en la documentación revisada","appearanceStatus":"provisional","appearanceBasis":"Referencia visual de fotografías públicas de Jinhong Gas / fabricante. Apariencia provisional para coordinación; fotografías oficiales pueden orientar el color, pero no acreditan el material, el acabado ni el equipo concreto.","appearanceReferences":["jinhong-official-asu"],"note":"El perfil visual no confirma material, grado ni acabado del componente."} | {"status":"componente_independiente","note":"Objeto independiente seleccionable. Las caras se asignan una sola vez entre todos los componentes del conjunto.","parentEquipmentId":"AC1001C","isAssemblyIdentityCarrier":false} | {"elementId":"AC1001C--cad-region-005","ifcGuid":"0KAnEAw9HLxOaR0UO4Dwe9","ifcClass":"IfcBuildingElementProxy","buildingId":"process_plant","buildingName":"Planta de proceso","sourceDocumentId":"EQ-IMPLANTACION-20260430","sourceRepresentationKind":"equipmentComponent"} | {"layerId":"equipment","layerName":"Equipos","role":"Componente de equipo · cuerpo o accesorio","basis":"Clasificación por función del elemento; no modifica las especificaciones documentales."} | {"profileId":"equipment_light_gray","name":"Equipo · gris claro provisional","status":"provisional","basis":"Referencia visual de fotografías públicas de Jinhong Gas / fabricante. Apariencia provisional para coordinación; fotografías oficiales pueden orientar el color, pero no acreditan el material, el acabado ni el equipo concreto.","physicalMaterialUnchanged":true} | Equipos | No especificado | Equipos | Equipo · gris claro provisional | provisional | AC1001C--cad-region-005 | ["Componente separado de una reconstrucción documental del conjunto. Las alturas y detalles parciales conservan las limitaciones del fabricante registradas en parentEquipmentIssues.","Esta representación exterior no crea una chapa hueca ni añade componentes internos no documentados.","La pertenencia al conjunto no demuestra apoyo o anclaje directo a la cimentación."] | Geometría de coordinación. Los volúmenes de referencia y subcomponentes no son cantidades de material ni componentes de fabricación certificados. | Sin especificación de material en la documentación revisada | {"documentId":"EQ-IMPLANTACION-20260430","title":"Plano del fabricante: implantación de equipos","sheet":"LHD2609-GD01000 · espacio modelo","date":"2026-04-30","componentSourceHandles":["71365","7166E","7167F","71926","71928","721E1","721E4","724C3","724CC","724CE","724D9","72513","7252D","7252E","7252F","72531","729A2","729A3","729A5","729A8","72C01","72C02","7302A","73042","73078","730A8","730FF","73101","73103","73105","73106","73107","73110","73112","73114","73115","732E7","73401","73404","73405","73406","73407"]} | yes | equipment_light_gray | [0.88,0.89,0.88] | 0.45 | 0.28 | Referencia visual de fotografías públicas de Jinhong Gas / fabricante. Apariencia provisional para coordinación; fotografías oficiales pueden orientar el color, pero no acreditan el material, el acabado ni el equipo concreto. | La apariencia no certifica el material físico ni el acabado de fabricación. | BIM · Equipos | AC1001C | Compresor de aire AC1001C | IfcCompressor | {"documented":[{"label":"Dimensión X local del bastidor de referencia CAD","value":2.35,"unit":"m","source":"EQ-CARGAS-20260825 · contorno CAD · handles 3F0","status":"derivado"},{"label":"Dimensión Y local del bastidor de referencia CAD","value":5.22,"unit":"m","source":"EQ-CARGAS-20260825 · contorno CAD · handles 3F0","status":"derivado"},{"label":"Altura acotada","value":3.38,"unit":"m","source":"EQ-CARGAS-20260825 · handle 25AF","status":"documentado"},{"label":"Cota relativa de la superficie de apoyo","value":0.4,"unit":"m","source":"LHD2609-JG00100-20260904 · sección 1 / 1-1 · 28C35, 28C38, 28C3B, 28C89","status":"documentado"}],"geometry":[{"label":"Extensión de la malla en X","value":3.177584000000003,"unit":"m","source":"Geometría releída del IFC; datum absoluto de proceso provisional","status":"derivado"},{"label":"Extensión de la malla en Y","value":6.404527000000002,"unit":"m","source":"Geometría releída del IFC; datum absoluto de proceso provisional","status":"derivado"},{"label":"Extensión de la malla en Z","value":3.3800000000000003,"unit":"m","source":"Geometría releída del IFC; datum absoluto de proceso provisional","status":"derivado"},{"label":"Cota inferior de visualización","value":286.5,"unit":"m","source":"Geometría releída del IFC; datum absoluto de proceso provisional","status":"derivado"},{"label":"Cota superior de visualización","value":289.88,"unit":"m","source":"Geometría releída del IFC; datum absoluto de proceso provisional","status":"derivado"}],"notes":["Las extensiones de la malla se miden en los ejes del proyecto tras el giro de implantación; no sustituyen las dimensiones locales del fabricante.","La envolvente, su volumen y los espesores de visualización no son volúmenes de material ni cantidades de compra, construcción o fabricación.","Las dimensiones documentadas distinguen cotas explícitas y medidas extraídas de contornos CAD; las dimensiones geométricas describen únicamente la malla publicada.","Las extensiones de la malla refinada y las dimensiones documentadas del contorno o bastidor tienen distinto alcance; las cotas parciales del detalle son provisionales."]} | {"Estado de la planta":"Derivado del CAD y del giro de implantación","Nivel relativo del apoyo (m)":0.4,"Estado del nivel relativo":"Documentado en el plano de cimentaciones","Cero absoluto de visualización (m)":286.1,"Estado del cero absoluto":"Provisional","Cota del apoyo de visualización (m)":286.5,"Desplazamiento aplicado a la malla (m)":0.40000000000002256,"Criterio":"Nivel de apoyo relativo documentado. Se adopta el cero de proceso a 286,10 m solo para visualización; la equivalencia absoluta no está confirmada. No se añade un espesor de montaje sin cota del fabricante."} | ["La máquina está contenida en la envolvente de la cabina acústica; su superposición no acredita una interferencia física.","El bastidor CAD coincide con la referencia de 2,35 × 5,22 m del plano de cargas, pero cuerpos y auxiliares del detalle de abril sobresalen de esa referencia, hasta aproximadamente 1,048 m por el extremo sur y 0,246 m por el lado oeste. Extensión geométrica resultante: 2,595899 × 6,268101 × 3,38 m, derivada y pendiente de coordinación entre revisiones. Permanecen dentro de la cabina acústica. Compatibilidad de revisión pendiente de fabricante.","Todas las alturas parciales son hipótesis de visualización; solo la altura total de 3,38 m está acotada.","Las regiones del dibujo se usan como envolventes de cuerpos; la identificación funcional y la cota Z de cada pieza requieren verificación.","Pequeños taladros, tornillería y detalles interiores de las regiones no se extruyen como vacíos de fabricación.","El bastidor documentado mide 2,35 × 5,22 m. Los accesorios del detalle de abril sobresalen; el conjunto refinado ocupa aproximadamente 2,596 × 6,268 m en ejes del fabricante, pendiente de coordinación entre revisiones.","El acabado de grout HA-35 de 50 mm termina en +0,400; el hormigón termina en +0,350. La losa MAC contigua termina en +0,200.","El cero absoluto de la revisión no está definido; 286,10 m sigue siendo una hipótesis de coordinación.","Se alinea el punto inferior del conjunto del equipo, incluidos los pies ya representados, con la superficie de apoyo terminada; no se añade un espesor de calzos, placa o grout del fabricante no documentado."] | {"revision":"Detalle en planta de 2026-04-30 coordinado de forma preliminar con envolventes y alturas de 2026-08-25","status":"provisional","verticalRule":"Altura total documentada: 3,38 m. Plataforma gráfica de 0,15 m; los cuerpos extraídos de la planta reciben alturas provisionales entre 1,00 y 3,38 m, detalladas por subvolumen. No se dispone de alzado acotado de cada componente.","partCount":26,"source":{"documentId":"EQ-IMPLANTACION-20260430","title":"Plano del fabricante: implantación de equipos","sheet":"LHD2609-GD01000 · espacio modelo","date":"2026-04-30"},"heightSource":{"documentId":"EQ-CARGAS-20260825","title":"Plano del fabricante: cargas de equipos","sheet":"Espacio modelo","date":"2026-08-25"},"unconfirmedDimensions":["Todas las alturas parciales son hipótesis de visualización; solo la altura total de 3,38 m está acotada.","Las regiones del dibujo se usan como envolventes de cuerpos; la identificación funcional y la cota Z de cada pieza requieren verificación.","Pequeños taladros, tornillería y detalles interiores de las regiones no se extruyen como vacíos de fabricación."],"quantityUse":"Magnitudes de la geometría representada; no son cantidades de material, obra, compra, capacidad útil ni fabricación. En geometrías compuestas se suman superficies y volúmenes de partes y pueden existir solapes no depurados.","partsAreBOM":false} | equipment_component | {"min":[60.820401,68.378413,1.5],"max":[63.997985,74.78294,4.88]} | {"boundingBoxM":{"min":[60.820401,68.378413,1.5],"max":[63.997985,74.78294,4.88]},"extentsM":[3.177584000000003,6.404527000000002,3.38],"meshSurfaceM2":165.19823143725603,"meshVolumeM3":20.170106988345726,"closedSolid":true,"windingConsistent":true,"basis":"Submalla exacta de los triángulos del modelo IFC coordinado; separación de componentes sin transformación ni retesselación."} | ["Todas las alturas parciales son hipótesis de visualización; solo la altura total de 3,38 m está acotada.","Las regiones del dibujo se usan como envolventes de cuerpos; la identificación funcional y la cota Z de cada pieza requieren verificación.","Pequeños taladros, tornillería y detalles interiores de las regiones no se extruyen como vacíos de fabricación.","La separación gráfica no aporta cotas de fabricación ni identifica piezas internas no documentadas.","Los materiales y acabados permanecen provisionales; las fotografías públicas solo orientan la apariencia."] | {"id":"AC1001C--cad-region-005","sourcePartId":"AC1001C--cad-region-005","name":"Cuerpo de equipo · región CAD 5","role":"equipment_component","classificationStatus":"provisional","classificationBasis":"Rol del subvolumen gráfico según el activo de detalle; identidad de fabricación no confirmada.","parentEquipmentId":"AC1001C","parentEquipmentGuid":"2IJ0PLLizIvfouRXAkczXf","isAssemblyIdentityCarrier":false,"sourceFaceRange":[140,160],"sourceCurrentFaceIndices":[140,141,142,143,144,145,146,147,148,149,150,151,152,153,154,155,156,157,158,159],"sourceMeshSha256":"7b60c904c9d84d22fded9be34af09a09a9c198ec8e75e61902634d5e4064c761","sourceVertexIndices":[80,81,82,83,84,85,86,87,88,89,90,91],"separationMethod":"Partición exacta de triángulos existentes; coordenadas y orientación de caras conservadas.","quantityUse":"Magnitudes geométricas del subvolumen; no son cantidades netas de material, fabricación, suministro o capacidad."} | {"id":"AC1001C","name":"Compresor de aire AC1001C","relationship":"decomposed_component","parentShapeMeaning":"La forma del objeto que conserva el ID del equipo es únicamente su componente principal; el conjunto completo requiere sus hijos."} | {"kind":"through_parent","parentEquipmentId":"AC1001C","directAnchorageVerified":false,"note":"La relación del conjunto con cimentaciones se conserva en el objeto que mantiene el ID del equipo; no se atribuye fijación directa a cada subcomponente."} | Documento de implantación y apoyo del conjunto padre; no acredita fijación individual de este componente. | AC1001C--cad-region-005 | Cuerpo de equipo · región CAD 5 | Equipos | unknown | equipment_light_gray | {"documentId":"EQ-IMPLANTACION-20260430","title":"Plano del fabricante: implantación de equipos","sheet":"LHD2609-GD01000 · espacio modelo","date":"2026-04-30","componentSourceHandles":["71365","7166E","7167F","71926","71928","721E1","721E4","724C3","724CC","724CE","724D9","72513","7252D","7252E","7252F","72531","729A2","729A3","729A5","729A8","72C01","72C02","7302A","73042","73078","730A8","730FF","73101","73103","73105","73106","73107","73110","73112","73114","73115","732E7","73401","73404","73405","73406","73407"]} | Submalla de triángulos existentes; no hay nueva posición ni nuevas caras. | Cotas globales del conjunto conservadas aparte; las dimensiones de esta ficha son de la submalla. | Coordinación del conjunto padre; anclaje directo individual no acreditado. | Superficie y volumen geométricos brutos; no constituyen cantidades netas de obra, material o fabricación. | Plano general y dimensiones globales de AC1001C; no se asignan esas dimensiones globales a este componente. | ["71365","7166E","7167F","71926","71928","721E1","721E4","724C3","724CC","724CE","724D9","72513","7252D","7252E","7252F","72531","729A2","729A3","729A5","729A8","72C01","72C02","7302A","73042","73078","730A8","730FF","73101","73103","73105","73106","73107","73110","73112","73114","73115","732E7","73401","73404","73405","73406","73407"] | 1 | no | Submalla exacta; interpretación funcional y cotas parciales provisionales.
Compresor de aire AC1001C · Cuerpo de equipo · región CAD 6 | Componente de equipo · cuerpo o accesorio | Plano del fabricante: implantación de equipos · referencia E7 | 0.966993 | 0.631269 | 1.05 | 286.65 | 287.7 | 3.90704 | 0.487517 | Apoyo relativo +0.400 m; cero absoluto provisional | Componente de equipo · cuerpo o accesorio | equipmentComponent | {"name":"No especificado","source":"Sin especificación de material en la documentación revisada","status":"unknown"} | {"documented":[{"label":"Referencia dimensional del conjunto","value":"Plano general y dimensiones globales de AC1001C; no se asignan esas dimensiones globales a este componente.","unit":"","source":"EQ-IMPLANTACION-20260430 · LHD2609-GD01000 · espacio modelo","status":"referencia_del_conjunto"}],"geometry":[{"label":"Extensión de la malla en X","value":0.9669930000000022,"unit":"m","source":"Geometría releída del IFC; datum absoluto de proceso provisional","status":"derivado"},{"label":"Extensión de la malla en Y","value":0.6312690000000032,"unit":"m","source":"Geometría releída del IFC; datum absoluto de proceso provisional","status":"derivado"},{"label":"Extensión de la malla en Z","value":1.0500000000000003,"unit":"m","source":"Geometría releída del IFC; datum absoluto de proceso provisional","status":"derivado"},{"label":"Cota inferior de visualización","value":286.65,"unit":"m","source":"Geometría releída del IFC; datum absoluto de proceso provisional","status":"derivado"},{"label":"Cota superior de visualización","value":287.7,"unit":"m","source":"Geometría releída del IFC; datum absoluto de proceso provisional","status":"derivado"}],"notes":["Las dimensiones del equipo completo se conservan en parentEquipmentDimensions.","Las extensiones en X/Y son de los ejes del modelo y no sustituyen cotas locales de fabricación.","No se infieren espesores de chapa, tolerancias ni dimensiones de piezas a partir de la partición."]} | {"documentId":"EQ-IMPLANTACION-20260430","title":"Plano del fabricante: implantación de equipos","sheet":"LHD2609-GD01000 · espacio modelo","date":"2026-04-30","componentSourceHandles":["732EB","732EC","732ED","732EE","732EF","732F0","732F1","732F2","73302","73305","73306","73307","73308","7330A","7330B","7330D","7330E","7330F","73310","73311","73312","73313","73322","73325","73326","73327","73328","73329","7332C","7332D","7332E","7332F","73332","73333","73334","73335","73337","73338","73339","7333E","7333F","73340","73341","73349","7334A","7334B","7334D","7334E","7334F","73350","73351","73352","73353","73354","73355","73356","73357","73359","7335A","7335B","7335D","73364","73365","73366","73367","73368","73369","7336A","7336B","7336C","7336D","7336E","7336F","73370","73372","73377","73378","7337C","7337D","7337E","73390","73398","73399","733A0","733A2","733A4","733A9","733AB","733AC","733AD","733B1","733B2","733B6","733B8","733B9","733BA","733C4","733CC","733D8","733DE","733DF","733E7","733E8","733E9","733F0","73403","734A4","734A5","734A7","734A8","734A9","734AA","734AB","734AC","734AD","734AE","734AF","734B0"]} | {"horizontalStatus":"derivado_del_conjunto","verticalStatus":"derivado_del_conjunto","coordinateSystem":"model_local_m","parentEquipmentId":"AC1001C","transformApplied":false,"note":"Coordenadas copiadas exactamente del equipo coordinado; no se ha movido, girado, elevado ni reescalado este componente.","foundationRelationship":"El apoyo y las cotas de instalación se documentan para el conjunto padre. Esta submalla no acredita un anclaje directo.","meshMinimumAbsoluteElevationM":286.65,"assemblyPlacementField":"parentEquipmentPositioning"} | ["Componente separado de una reconstrucción documental del conjunto. Las alturas y detalles parciales conservan las limitaciones del fabricante registradas en parentEquipmentIssues.","Esta representación exterior no crea una chapa hueca ni añade componentes internos no documentados.","La pertenencia al conjunto no demuestra apoyo o anclaje directo a la cimentación."] | {"source":{"documentId":"EQ-IMPLANTACION-20260430","title":"Plano del fabricante: implantación de equipos","sheet":"LHD2609-GD01000 · espacio modelo","date":"2026-04-30","componentSourceHandles":["732EB","732EC","732ED","732EE","732EF","732F0","732F1","732F2","73302","73305","73306","73307","73308","7330A","7330B","7330D","7330E","7330F","73310","73311","73312","73313","73322","73325","73326","73327","73328","73329","7332C","7332D","7332E","7332F","73332","73333","73334","73335","73337","73338","73339","7333E","7333F","73340","73341","73349","7334A","7334B","7334D","7334E","7334F","73350","73351","73352","73353","73354","73355","73356","73357","73359","7335A","7335B","7335D","73364","73365","73366","73367","73368","73369","7336A","7336B","7336C","7336D","7336E","7336F","73370","73372","73377","73378","7337C","7337D","7337E","73390","73398","73399","733A0","733A2","733A4","733A9","733AB","733AC","733AD","733B1","733B2","733B6","733B8","733B9","733BA","733C4","733CC","733D8","733DE","733DF","733E7","733E8","733E9","733F0","73403","734A4","734A5","734A7","734A8","734A9","734AA","734AB","734AC","734AD","734AE","734AF","734B0"]},"sourcePartId":"AC1001C--cad-region-006","sourceHandles":["732EB","732EC","732ED","732EE","732EF","732F0","732F1","732F2","73302","73305","73306","73307","73308","7330A","7330B","7330D","7330E","7330F","73310","73311","73312","73313","73322","73325","73326","73327","73328","73329","7332C","7332D","7332E","7332F","73332","73333","73334","73335","73337","73338","73339","7333E","7333F","73340","73341","73349","7334A","7334B","7334D","7334E","7334F","73350","73351","73352","73353","73354","73355","73356","73357","73359","7335A","7335B","7335D","73364","73365","73366","73367","73368","73369","7336A","7336B","7336C","7336D","7336E","7336F","73370","73372","73377","73378","7337C","7337D","7337E","73390","73398","73399","733A0","733A2","733A4","733A9","733AB","733AC","733AD","733B1","733B2","733B6","733B8","733B9","733BA","733C4","733CC","733D8","733DE","733DF","733E7","733E8","733E9","733F0","73403","734A4","734A5","734A7","734A8","734A9","734AA","734AB","734AC","734AD","734AE","734AF","734B0"],"partCount":1,"partsAreBOM":false,"status":"Submalla exacta; interpretación funcional y cotas parciales provisionales."} | {"boundingBoxM":{"min":[61.336154,68.378413,1.65],"max":[62.303147,69.009682,2.7]},"extentsM":[0.966993,0.631269,1.05],"meshSurfaceM2":3.907036,"meshVolumeM3":0.487517,"closedSolid":true,"basis":"Geometría de coordinación. Los volúmenes de referencia y subcomponentes no son cantidades de material ni componentes de fabricación certificados."} | {"documentId":"LHD2609-JG00100-20260904","title":"Cimentaciones y pedestales de equipos · revisión recibida 04/09/2026","date":"2026-09-04","sheet":"1 / 1-1","sourceHandles":["28C35","28C38","28C3B","28C89"]} | equipment | {"id":"equipment","name":"Equipos"} | {"profileId":"equipment_light_gray","name":"Equipo · gris claro provisional","materialName":"No especificado","physicalMaterialStatus":"unknown","physicalMaterialSource":"Sin especificación de material en la documentación revisada","appearanceStatus":"provisional","appearanceBasis":"Referencia visual de fotografías públicas de Jinhong Gas / fabricante. Apariencia provisional para coordinación; fotografías oficiales pueden orientar el color, pero no acreditan el material, el acabado ni el equipo concreto.","appearanceReferences":["jinhong-official-asu"],"note":"El perfil visual no confirma material, grado ni acabado del componente."} | {"status":"componente_independiente","note":"Objeto independiente seleccionable. Las caras se asignan una sola vez entre todos los componentes del conjunto.","parentEquipmentId":"AC1001C","isAssemblyIdentityCarrier":false} | {"elementId":"AC1001C--cad-region-006","ifcGuid":"0PJM$3MezJOAVMmDmmriuz","ifcClass":"IfcBuildingElementProxy","buildingId":"process_plant","buildingName":"Planta de proceso","sourceDocumentId":"EQ-IMPLANTACION-20260430","sourceRepresentationKind":"equipmentComponent"} | {"layerId":"equipment","layerName":"Equipos","role":"Componente de equipo · cuerpo o accesorio","basis":"Clasificación por función del elemento; no modifica las especificaciones documentales."} | {"profileId":"equipment_light_gray","name":"Equipo · gris claro provisional","status":"provisional","basis":"Referencia visual de fotografías públicas de Jinhong Gas / fabricante. Apariencia provisional para coordinación; fotografías oficiales pueden orientar el color, pero no acreditan el material, el acabado ni el equipo concreto.","physicalMaterialUnchanged":true} | Equipos | No especificado | Equipos | Equipo · gris claro provisional | provisional | AC1001C--cad-region-006 | ["Componente separado de una reconstrucción documental del conjunto. Las alturas y detalles parciales conservan las limitaciones del fabricante registradas en parentEquipmentIssues.","Esta representación exterior no crea una chapa hueca ni añade componentes internos no documentados.","La pertenencia al conjunto no demuestra apoyo o anclaje directo a la cimentación."] | Geometría de coordinación. Los volúmenes de referencia y subcomponentes no son cantidades de material ni componentes de fabricación certificados. | Sin especificación de material en la documentación revisada | {"documentId":"EQ-IMPLANTACION-20260430","title":"Plano del fabricante: implantación de equipos","sheet":"LHD2609-GD01000 · espacio modelo","date":"2026-04-30","componentSourceHandles":["732EB","732EC","732ED","732EE","732EF","732F0","732F1","732F2","73302","73305","73306","73307","73308","7330A","7330B","7330D","7330E","7330F","73310","73311","73312","73313","73322","73325","73326","73327","73328","73329","7332C","7332D","7332E","7332F","73332","73333","73334","73335","73337","73338","73339","7333E","7333F","73340","73341","73349","7334A","7334B","7334D","7334E","7334F","73350","73351","73352","73353","73354","73355","73356","73357","73359","7335A","7335B","7335D","73364","73365","73366","73367","73368","73369","7336A","7336B","7336C","7336D","7336E","7336F","73370","73372","73377","73378","7337C","7337D","7337E","73390","73398","73399","733A0","733A2","733A4","733A9","733AB","733AC","733AD","733B1","733B2","733B6","733B8","733B9","733BA","733C4","733CC","733D8","733DE","733DF","733E7","733E8","733E9","733F0","73403","734A4","734A5","734A7","734A8","734A9","734AA","734AB","734AC","734AD","734AE","734AF","734B0"]} | yes | equipment_light_gray | [0.88,0.89,0.88] | 0.45 | 0.28 | Referencia visual de fotografías públicas de Jinhong Gas / fabricante. Apariencia provisional para coordinación; fotografías oficiales pueden orientar el color, pero no acreditan el material, el acabado ni el equipo concreto. | La apariencia no certifica el material físico ni el acabado de fabricación. | BIM · Equipos | AC1001C | Compresor de aire AC1001C | IfcCompressor | {"documented":[{"label":"Dimensión X local del bastidor de referencia CAD","value":2.35,"unit":"m","source":"EQ-CARGAS-20260825 · contorno CAD · handles 3F0","status":"derivado"},{"label":"Dimensión Y local del bastidor de referencia CAD","value":5.22,"unit":"m","source":"EQ-CARGAS-20260825 · contorno CAD · handles 3F0","status":"derivado"},{"label":"Altura acotada","value":3.38,"unit":"m","source":"EQ-CARGAS-20260825 · handle 25AF","status":"documentado"},{"label":"Cota relativa de la superficie de apoyo","value":0.4,"unit":"m","source":"LHD2609-JG00100-20260904 · sección 1 / 1-1 · 28C35, 28C38, 28C3B, 28C89","status":"documentado"}],"geometry":[{"label":"Extensión de la malla en X","value":3.177584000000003,"unit":"m","source":"Geometría releída del IFC; datum absoluto de proceso provisional","status":"derivado"},{"label":"Extensión de la malla en Y","value":6.404527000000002,"unit":"m","source":"Geometría releída del IFC; datum absoluto de proceso provisional","status":"derivado"},{"label":"Extensión de la malla en Z","value":3.3800000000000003,"unit":"m","source":"Geometría releída del IFC; datum absoluto de proceso provisional","status":"derivado"},{"label":"Cota inferior de visualización","value":286.5,"unit":"m","source":"Geometría releída del IFC; datum absoluto de proceso provisional","status":"derivado"},{"label":"Cota superior de visualización","value":289.88,"unit":"m","source":"Geometría releída del IFC; datum absoluto de proceso provisional","status":"derivado"}],"notes":["Las extensiones de la malla se miden en los ejes del proyecto tras el giro de implantación; no sustituyen las dimensiones locales del fabricante.","La envolvente, su volumen y los espesores de visualización no son volúmenes de material ni cantidades de compra, construcción o fabricación.","Las dimensiones documentadas distinguen cotas explícitas y medidas extraídas de contornos CAD; las dimensiones geométricas describen únicamente la malla publicada.","Las extensiones de la malla refinada y las dimensiones documentadas del contorno o bastidor tienen distinto alcance; las cotas parciales del detalle son provisionales."]} | {"Estado de la planta":"Derivado del CAD y del giro de implantación","Nivel relativo del apoyo (m)":0.4,"Estado del nivel relativo":"Documentado en el plano de cimentaciones","Cero absoluto de visualización (m)":286.1,"Estado del cero absoluto":"Provisional","Cota del apoyo de visualización (m)":286.5,"Desplazamiento aplicado a la malla (m)":0.40000000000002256,"Criterio":"Nivel de apoyo relativo documentado. Se adopta el cero de proceso a 286,10 m solo para visualización; la equivalencia absoluta no está confirmada. No se añade un espesor de montaje sin cota del fabricante."} | ["La máquina está contenida en la envolvente de la cabina acústica; su superposición no acredita una interferencia física.","El bastidor CAD coincide con la referencia de 2,35 × 5,22 m del plano de cargas, pero cuerpos y auxiliares del detalle de abril sobresalen de esa referencia, hasta aproximadamente 1,048 m por el extremo sur y 0,246 m por el lado oeste. Extensión geométrica resultante: 2,595899 × 6,268101 × 3,38 m, derivada y pendiente de coordinación entre revisiones. Permanecen dentro de la cabina acústica. Compatibilidad de revisión pendiente de fabricante.","Todas las alturas parciales son hipótesis de visualización; solo la altura total de 3,38 m está acotada.","Las regiones del dibujo se usan como envolventes de cuerpos; la identificación funcional y la cota Z de cada pieza requieren verificación.","Pequeños taladros, tornillería y detalles interiores de las regiones no se extruyen como vacíos de fabricación.","El bastidor documentado mide 2,35 × 5,22 m. Los accesorios del detalle de abril sobresalen; el conjunto refinado ocupa aproximadamente 2,596 × 6,268 m en ejes del fabricante, pendiente de coordinación entre revisiones.","El acabado de grout HA-35 de 50 mm termina en +0,400; el hormigón termina en +0,350. La losa MAC contigua termina en +0,200.","El cero absoluto de la revisión no está definido; 286,10 m sigue siendo una hipótesis de coordinación.","Se alinea el punto inferior del conjunto del equipo, incluidos los pies ya representados, con la superficie de apoyo terminada; no se añade un espesor de calzos, placa o grout del fabricante no documentado."] | {"revision":"Detalle en planta de 2026-04-30 coordinado de forma preliminar con envolventes y alturas de 2026-08-25","status":"provisional","verticalRule":"Altura total documentada: 3,38 m. Plataforma gráfica de 0,15 m; los cuerpos extraídos de la planta reciben alturas provisionales entre 1,00 y 3,38 m, detalladas por subvolumen. No se dispone de alzado acotado de cada componente.","partCount":26,"source":{"documentId":"EQ-IMPLANTACION-20260430","title":"Plano del fabricante: implantación de equipos","sheet":"LHD2609-GD01000 · espacio modelo","date":"2026-04-30"},"heightSource":{"documentId":"EQ-CARGAS-20260825","title":"Plano del fabricante: cargas de equipos","sheet":"Espacio modelo","date":"2026-08-25"},"unconfirmedDimensions":["Todas las alturas parciales son hipótesis de visualización; solo la altura total de 3,38 m está acotada.","Las regiones del dibujo se usan como envolventes de cuerpos; la identificación funcional y la cota Z de cada pieza requieren verificación.","Pequeños taladros, tornillería y detalles interiores de las regiones no se extruyen como vacíos de fabricación."],"quantityUse":"Magnitudes de la geometría representada; no son cantidades de material, obra, compra, capacidad útil ni fabricación. En geometrías compuestas se suman superficies y volúmenes de partes y pueden existir solapes no depurados.","partsAreBOM":false} | equipment_component | {"min":[60.820401,68.378413,1.5],"max":[63.997985,74.78294,4.88]} | {"boundingBoxM":{"min":[60.820401,68.378413,1.5],"max":[63.997985,74.78294,4.88]},"extentsM":[3.177584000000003,6.404527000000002,3.38],"meshSurfaceM2":165.19823143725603,"meshVolumeM3":20.170106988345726,"closedSolid":true,"windingConsistent":true,"basis":"Submalla exacta de los triángulos del modelo IFC coordinado; separación de componentes sin transformación ni retesselación."} | ["Todas las alturas parciales son hipótesis de visualización; solo la altura total de 3,38 m está acotada.","Las regiones del dibujo se usan como envolventes de cuerpos; la identificación funcional y la cota Z de cada pieza requieren verificación.","Pequeños taladros, tornillería y detalles interiores de las regiones no se extruyen como vacíos de fabricación.","La separación gráfica no aporta cotas de fabricación ni identifica piezas internas no documentadas.","Los materiales y acabados permanecen provisionales; las fotografías públicas solo orientan la apariencia."] | {"id":"AC1001C--cad-region-006","sourcePartId":"AC1001C--cad-region-006","name":"Cuerpo de equipo · región CAD 6","role":"equipment_component","classificationStatus":"provisional","classificationBasis":"Rol del subvolumen gráfico según el activo de detalle; identidad de fabricación no confirmada.","parentEquipmentId":"AC1001C","parentEquipmentGuid":"2IJ0PLLizIvfouRXAkczXf","isAssemblyIdentityCarrier":false,"sourceFaceRange":[160,172],"sourceCurrentFaceIndices":[160,161,162,163,164,165,166,167,168,169,170,171],"sourceMeshSha256":"7b60c904c9d84d22fded9be34af09a09a9c198ec8e75e61902634d5e4064c761","sourceVertexIndices":[92,93,94,95,96,97,98,99],"separationMethod":"Partición exacta de triángulos existentes; coordenadas y orientación de caras conservadas.","quantityUse":"Magnitudes geométricas del subvolumen; no son cantidades netas de material, fabricación, suministro o capacidad."} | {"id":"AC1001C","name":"Compresor de aire AC1001C","relationship":"decomposed_component","parentShapeMeaning":"La forma del objeto que conserva el ID del equipo es únicamente su componente principal; el conjunto completo requiere sus hijos."} | {"kind":"through_parent","parentEquipmentId":"AC1001C","directAnchorageVerified":false,"note":"La relación del conjunto con cimentaciones se conserva en el objeto que mantiene el ID del equipo; no se atribuye fijación directa a cada subcomponente."} | Documento de implantación y apoyo del conjunto padre; no acredita fijación individual de este componente. | AC1001C--cad-region-006 | Cuerpo de equipo · región CAD 6 | Equipos | unknown | equipment_light_gray | {"documentId":"EQ-IMPLANTACION-20260430","title":"Plano del fabricante: implantación de equipos","sheet":"LHD2609-GD01000 · espacio modelo","date":"2026-04-30","componentSourceHandles":["732EB","732EC","732ED","732EE","732EF","732F0","732F1","732F2","73302","73305","73306","73307","73308","7330A","7330B","7330D","7330E","7330F","73310","73311","73312","73313","73322","73325","73326","73327","73328","73329","7332C","7332D","7332E","7332F","73332","73333","73334","73335","73337","73338","73339","7333E","7333F","73340","73341","73349","7334A","7334B","7334D","7334E","7334F","73350","73351","73352","73353","73354","73355","73356","73357","73359","7335A","7335B","7335D","73364","73365","73366","73367","73368","73369","7336A","7336B","7336C","7336D","7336E","7336F","73370","73372","73377","73378","7337C","7337D","7337E","73390","73398","73399","733A0","733A2","733A4","733A9","733AB","733AC","733AD","733B1","733B2","733B6","733B8","733B9","733BA","733C4","733CC","733D8","733DE","733DF","733E7","733E8","733E9","733F0","73403","734A4","734A5","734A7","734A8","734A9","734AA","734AB","734AC","734AD","734AE","734AF","734B0"]} | Submalla de triángulos existentes; no hay nueva posición ni nuevas caras. | Cotas globales del conjunto conservadas aparte; las dimensiones de esta ficha son de la submalla. | Coordinación del conjunto padre; anclaje directo individual no acreditado. | Superficie y volumen geométricos brutos; no constituyen cantidades netas de obra, material o fabricación. | Plano general y dimensiones globales de AC1001C; no se asignan esas dimensiones globales a este componente. | ["732EB","732EC","732ED","732EE","732EF","732F0","732F1","732F2","73302","73305","73306","73307","73308","7330A","7330B","7330D","7330E","7330F","73310","73311","73312","73313","73322","73325","73326","73327","73328","73329","7332C","7332D","7332E","7332F","73332","73333","73334","73335","73337","73338","73339","7333E","7333F","73340","73341","73349","7334A","7334B","7334D","7334E","7334F","73350","73351","73352","73353","73354","73355","73356","73357","73359","7335A","7335B","7335D","73364","73365","73366","73367","73368","73369","7336A","7336B","7336C","7336D","7336E","7336F","73370","73372","73377","73378","7337C","7337D","7337E","73390","73398","73399","733A0","733A2","733A4","733A9","733AB","733AC","733AD","733B1","733B2","733B6","733B8","733B9","733BA","733C4","733CC","733D8","733DE","733DF","733E7","733E8","733E9","733F0","73403","734A4","734A5","734A7","734A8","734A9","734AA","734AB","734AC","734AD","734AE","734AF","734B0"] | 1 | no | Submalla exacta; interpretación funcional y cotas parciales provisionales.
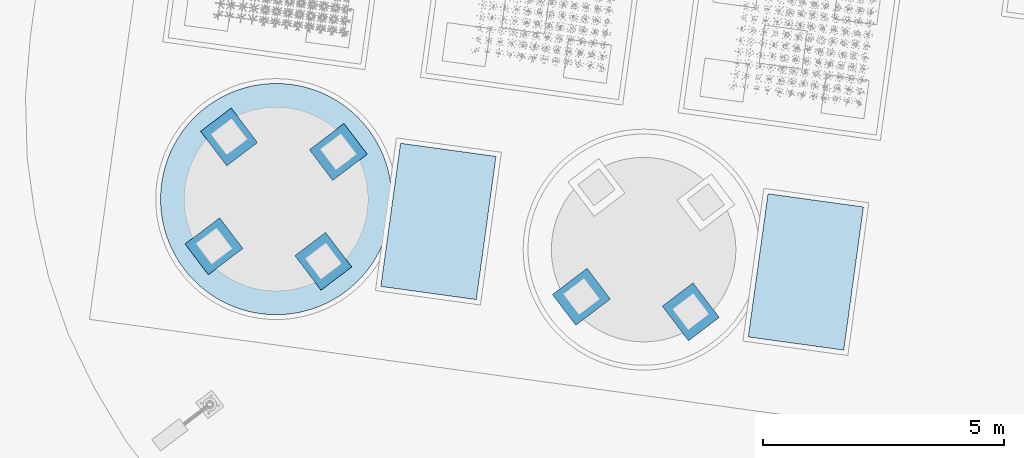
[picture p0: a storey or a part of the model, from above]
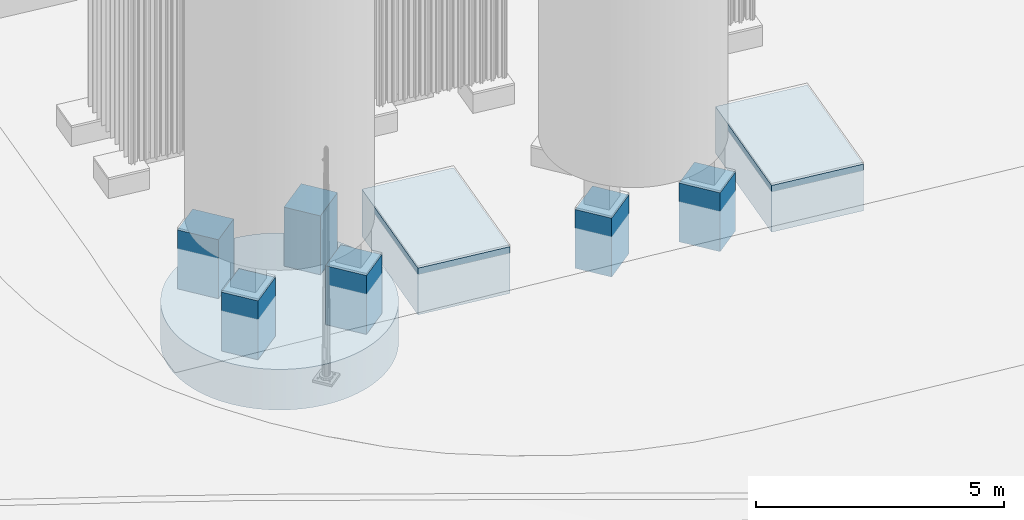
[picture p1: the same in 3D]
Properties of the parts of a building model (IFC4), part 44 of 134

# IfcBuildingElementProxy (140)
Name | Description | Document | Extensión de la malla en X (m) = ExtensionX (m) | Extensión de la malla en Y (m) = ExtensionY (m) | Extensión de la malla en Z (m) = ExtensionZ (m) | Cota inferior de visualización (m) | Cota superior de visualización (m) | SuperficieDeLaMalla (m2) | VolumenGeometrico (m3) | level | category = Categoria = Funcion | representationKind | material | dimensions | JH_InformacionBIM, source = DocumentoFuente | positioning = PosicionYEstado | issues | detailGeometry | geometryMetrics | installationSource | layerId = IdentificadorCapa | visualLayer | materialAppearance | componentSeparation | visualizationIdentity | classification | appearance | Disciplina | Material | Capa BIM = NombreCapa | Acabado de visualización = Acabado | Estado del acabado = Estado | Identificador | JH_Trazabilidad, IncidenciasPendientes | UsoDeLasMagnitudes | JH_EvidenciaDeMaterial, source | JH_DetalleGeometrico, source | VisibilidadInicial | Perfil | ColorRGB | Rugosidad | Metallicidad | Referencia | Nota | Group | parentEquipmentId = Identificador del equipo padre | parentEquipmentName = Equipo padre | parentEquipmentIfcClass | parentEquipmentDimensions | parentEquipmentPositioning | parentEquipmentIssues | parentEquipmentDetail | componentRole = Rol del componente | assemblyBBox | assemblyGeometryMetrics | manufacturerDetailsPending | component | assembly | foundationRelationship | installationSourceScope | Identificador del elemento = sourcePartId | Componente | Capa de visualización | Estado del material | Perfil visual del material | Fuente del componente | Criterio de partición | Criterio de las dimensiones | Relación con cimentaciones | Aplicabilidad de las mediciones | Referencia dimensional del conjunto | sourceHandles | partCount | partsAreBOM | status
Compresor de aire AC1001C · Cuerpo de equipo · región CAD 7 | Componente de equipo · cuerpo o accesorio | Plano del fabricante: implantación de equipos · referencia E7 | 0.408346 | 1.02466 | 1.65 | 286.65 | 288.3 | 4.74221 | 0.453154 | Apoyo relativo +0.400 m; cero absoluto provisional | Componente de equipo · cuerpo o accesorio | equipmentComponent | {"name":"No especificado","source":"Sin especificación de material en la documentación revisada","status":"unknown"} | {"documented":[{"label":"Referencia dimensional del conjunto","value":"Plano general y dimensiones globales de AC1001C; no se asignan esas dimensiones globales a este componente.","unit":"","source":"EQ-IMPLANTACION-20260430 · LHD2609-GD01000 · espacio modelo","status":"referencia_del_conjunto"}],"geometry":[{"label":"Extensión de la malla en X","value":0.40834600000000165,"unit":"m","source":"Geometría releída del IFC; datum absoluto de proceso provisional","status":"derivado"},{"label":"Extensión de la malla en Y","value":1.0246570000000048,"unit":"m","source":"Geometría releída del IFC; datum absoluto de proceso provisional","status":"derivado"},{"label":"Extensión de la malla en Z","value":1.65,"unit":"m","source":"Geometría releída del IFC; datum absoluto de proceso provisional","status":"derivado"},{"label":"Cota inferior de visualización","value":286.65,"unit":"m","source":"Geometría releída del IFC; datum absoluto de proceso provisional","status":"derivado"},{"label":"Cota superior de visualización","value":288.3,"unit":"m","source":"Geometría releída del IFC; datum absoluto de proceso provisional","status":"derivado"}],"notes":["Las dimensiones del equipo completo se conservan en parentEquipmentDimensions.","Las extensiones en X/Y son de los ejes del modelo y no sustituyen cotas locales de fabricación.","No se infieren espesores de chapa, tolerancias ni dimensiones de piezas a partir de la partición."]} | {"documentId":"EQ-IMPLANTACION-20260430","title":"Plano del fabricante: implantación de equipos","sheet":"LHD2609-GD01000 · espacio modelo","date":"2026-04-30","componentSourceHandles":["729DA","729DB","72A33","72A34","72A35","72A3C","72A45","72A46","72A47","72A48","72A49","72A4E","72A4F","72A50"]} | {"horizontalStatus":"derivado_del_conjunto","verticalStatus":"derivado_del_conjunto","coordinateSystem":"model_local_m","parentEquipmentId":"AC1001C","transformApplied":false,"note":"Coordenadas copiadas exactamente del equipo coordinado; no se ha movido, girado, elevado ni reescalado este componente.","foundationRelationship":"El apoyo y las cotas de instalación se documentan para el conjunto padre. Esta submalla no acredita un anclaje directo.","meshMinimumAbsoluteElevationM":286.65,"assemblyPlacementField":"parentEquipmentPositioning"} | ["Componente separado de una reconstrucción documental del conjunto. Las alturas y detalles parciales conservan las limitaciones del fabricante registradas en parentEquipmentIssues.","Esta representación exterior no crea una chapa hueca ni añade componentes internos no documentados.","La pertenencia al conjunto no demuestra apoyo o anclaje directo a la cimentación."] | {"source":{"documentId":"EQ-IMPLANTACION-20260430","title":"Plano del fabricante: implantación de equipos","sheet":"LHD2609-GD01000 · espacio modelo","date":"2026-04-30","componentSourceHandles":["729DA","729DB","72A33","72A34","72A35","72A3C","72A45","72A46","72A47","72A48","72A49","72A4E","72A4F","72A50"]},"sourcePartId":"AC1001C--cad-region-007","sourceHandles":["729DA","729DB","72A33","72A34","72A35","72A3C","72A45","72A46","72A47","72A48","72A49","72A4E","72A4F","72A50"],"partCount":1,"partsAreBOM":false,"status":"Submalla exacta; interpretación funcional y cotas parciales provisionales."} | {"boundingBoxM":{"min":[62.958766,69.436932,1.65],"max":[63.367112,70.461589,3.3]},"extentsM":[0.408346,1.024657,1.65],"meshSurfaceM2":4.742215,"meshVolumeM3":0.453154,"closedSolid":true,"basis":"Geometría de coordinación. Los volúmenes de referencia y subcomponentes no son cantidades de material ni componentes de fabricación certificados."} | {"documentId":"LHD2609-JG00100-20260904","title":"Cimentaciones y pedestales de equipos · revisión recibida 04/09/2026","date":"2026-09-04","sheet":"1 / 1-1","sourceHandles":["28C35","28C38","28C3B","28C89"]} | equipment | {"id":"equipment","name":"Equipos"} | {"profileId":"equipment_light_gray","name":"Equipo · gris claro provisional","materialName":"No especificado","physicalMaterialStatus":"unknown","physicalMaterialSource":"Sin especificación de material en la documentación revisada","appearanceStatus":"provisional","appearanceBasis":"Referencia visual de fotografías públicas de Jinhong Gas / fabricante. Apariencia provisional para coordinación; fotografías oficiales pueden orientar el color, pero no acreditan el material, el acabado ni el equipo concreto.","appearanceReferences":["jinhong-official-asu"],"note":"El perfil visual no confirma material, grado ni acabado del componente."} | {"status":"componente_independiente","note":"Objeto independiente seleccionable. Las caras se asignan una sola vez entre todos los componentes del conjunto.","parentEquipmentId":"AC1001C","isAssemblyIdentityCarrier":false} | {"elementId":"AC1001C--cad-region-007","ifcGuid":"2vsHlryc9MoAiY1nU6VJO0","ifcClass":"IfcBuildingElementProxy","buildingId":"process_plant","buildingName":"Planta de proceso","sourceDocumentId":"EQ-IMPLANTACION-20260430","sourceRepresentationKind":"equipmentComponent"} | {"layerId":"equipment","layerName":"Equipos","role":"Componente de equipo · cuerpo o accesorio","basis":"Clasificación por función del elemento; no modifica las especificaciones documentales."} | {"profileId":"equipment_light_gray","name":"Equipo · gris claro provisional","status":"provisional","basis":"Referencia visual de fotografías públicas de Jinhong Gas / fabricante. Apariencia provisional para coordinación; fotografías oficiales pueden orientar el color, pero no acreditan el material, el acabado ni el equipo concreto.","physicalMaterialUnchanged":true} | Equipos | No especificado | Equipos | Equipo · gris claro provisional | provisional | AC1001C--cad-region-007 | ["Componente separado de una reconstrucción documental del conjunto. Las alturas y detalles parciales conservan las limitaciones del fabricante registradas en parentEquipmentIssues.","Esta representación exterior no crea una chapa hueca ni añade componentes internos no documentados.","La pertenencia al conjunto no demuestra apoyo o anclaje directo a la cimentación."] | Geometría de coordinación. Los volúmenes de referencia y subcomponentes no son cantidades de material ni componentes de fabricación certificados. | Sin especificación de material en la documentación revisada | {"documentId":"EQ-IMPLANTACION-20260430","title":"Plano del fabricante: implantación de equipos","sheet":"LHD2609-GD01000 · espacio modelo","date":"2026-04-30","componentSourceHandles":["729DA","729DB","72A33","72A34","72A35","72A3C","72A45","72A46","72A47","72A48","72A49","72A4E","72A4F","72A50"]} | yes | equipment_light_gray | [0.88,0.89,0.88] | 0.45 | 0.28 | Referencia visual de fotografías públicas de Jinhong Gas / fabricante. Apariencia provisional para coordinación; fotografías oficiales pueden orientar el color, pero no acreditan el material, el acabado ni el equipo concreto. | La apariencia no certifica el material físico ni el acabado de fabricación. | BIM · Equipos | AC1001C | Compresor de aire AC1001C | IfcCompressor | {"documented":[{"label":"Dimensión X local del bastidor de referencia CAD","value":2.35,"unit":"m","source":"EQ-CARGAS-20260825 · contorno CAD · handles 3F0","status":"derivado"},{"label":"Dimensión Y local del bastidor de referencia CAD","value":5.22,"unit":"m","source":"EQ-CARGAS-20260825 · contorno CAD · handles 3F0","status":"derivado"},{"label":"Altura acotada","value":3.38,"unit":"m","source":"EQ-CARGAS-20260825 · handle 25AF","status":"documentado"},{"label":"Cota relativa de la superficie de apoyo","value":0.4,"unit":"m","source":"LHD2609-JG00100-20260904 · sección 1 / 1-1 · 28C35, 28C38, 28C3B, 28C89","status":"documentado"}],"geometry":[{"label":"Extensión de la malla en X","value":3.177584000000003,"unit":"m","source":"Geometría releída del IFC; datum absoluto de proceso provisional","status":"derivado"},{"label":"Extensión de la malla en Y","value":6.404527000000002,"unit":"m","source":"Geometría releída del IFC; datum absoluto de proceso provisional","status":"derivado"},{"label":"Extensión de la malla en Z","value":3.3800000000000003,"unit":"m","source":"Geometría releída del IFC; datum absoluto de proceso provisional","status":"derivado"},{"label":"Cota inferior de visualización","value":286.5,"unit":"m","source":"Geometría releída del IFC; datum absoluto de proceso provisional","status":"derivado"},{"label":"Cota superior de visualización","value":289.88,"unit":"m","source":"Geometría releída del IFC; datum absoluto de proceso provisional","status":"derivado"}],"notes":["Las extensiones de la malla se miden en los ejes del proyecto tras el giro de implantación; no sustituyen las dimensiones locales del fabricante.","La envolvente, su volumen y los espesores de visualización no son volúmenes de material ni cantidades de compra, construcción o fabricación.","Las dimensiones documentadas distinguen cotas explícitas y medidas extraídas de contornos CAD; las dimensiones geométricas describen únicamente la malla publicada.","Las extensiones de la malla refinada y las dimensiones documentadas del contorno o bastidor tienen distinto alcance; las cotas parciales del detalle son provisionales."]} | {"Estado de la planta":"Derivado del CAD y del giro de implantación","Nivel relativo del apoyo (m)":0.4,"Estado del nivel relativo":"Documentado en el plano de cimentaciones","Cero absoluto de visualización (m)":286.1,"Estado del cero absoluto":"Provisional","Cota del apoyo de visualización (m)":286.5,"Desplazamiento aplicado a la malla (m)":0.40000000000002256,"Criterio":"Nivel de apoyo relativo documentado. Se adopta el cero de proceso a 286,10 m solo para visualización; la equivalencia absoluta no está confirmada. No se añade un espesor de montaje sin cota del fabricante."} | ["La máquina está contenida en la envolvente de la cabina acústica; su superposición no acredita una interferencia física.","El bastidor CAD coincide con la referencia de 2,35 × 5,22 m del plano de cargas, pero cuerpos y auxiliares del detalle de abril sobresalen de esa referencia, hasta aproximadamente 1,048 m por el extremo sur y 0,246 m por el lado oeste. Extensión geométrica resultante: 2,595899 × 6,268101 × 3,38 m, derivada y pendiente de coordinación entre revisiones. Permanecen dentro de la cabina acústica. Compatibilidad de revisión pendiente de fabricante.","Todas las alturas parciales son hipótesis de visualización; solo la altura total de 3,38 m está acotada.","Las regiones del dibujo se usan como envolventes de cuerpos; la identificación funcional y la cota Z de cada pieza requieren verificación.","Pequeños taladros, tornillería y detalles interiores de las regiones no se extruyen como vacíos de fabricación.","El bastidor documentado mide 2,35 × 5,22 m. Los accesorios del detalle de abril sobresalen; el conjunto refinado ocupa aproximadamente 2,596 × 6,268 m en ejes del fabricante, pendiente de coordinación entre revisiones.","El acabado de grout HA-35 de 50 mm termina en +0,400; el hormigón termina en +0,350. La losa MAC contigua termina en +0,200.","El cero absoluto de la revisión no está definido; 286,10 m sigue siendo una hipótesis de coordinación.","Se alinea el punto inferior del conjunto del equipo, incluidos los pies ya representados, con la superficie de apoyo terminada; no se añade un espesor de calzos, placa o grout del fabricante no documentado."] | {"revision":"Detalle en planta de 2026-04-30 coordinado de forma preliminar con envolventes y alturas de 2026-08-25","status":"provisional","verticalRule":"Altura total documentada: 3,38 m. Plataforma gráfica de 0,15 m; los cuerpos extraídos de la planta reciben alturas provisionales entre 1,00 y 3,38 m, detalladas por subvolumen. No se dispone de alzado acotado de cada componente.","partCount":26,"source":{"documentId":"EQ-IMPLANTACION-20260430","title":"Plano del fabricante: implantación de equipos","sheet":"LHD2609-GD01000 · espacio modelo","date":"2026-04-30"},"heightSource":{"documentId":"EQ-CARGAS-20260825","title":"Plano del fabricante: cargas de equipos","sheet":"Espacio modelo","date":"2026-08-25"},"unconfirmedDimensions":["Todas las alturas parciales son hipótesis de visualización; solo la altura total de 3,38 m está acotada.","Las regiones del dibujo se usan como envolventes de cuerpos; la identificación funcional y la cota Z de cada pieza requieren verificación.","Pequeños taladros, tornillería y detalles interiores de las regiones no se extruyen como vacíos de fabricación."],"quantityUse":"Magnitudes de la geometría representada; no son cantidades de material, obra, compra, capacidad útil ni fabricación. En geometrías compuestas se suman superficies y volúmenes de partes y pueden existir solapes no depurados.","partsAreBOM":false} | equipment_component | {"min":[60.820401,68.378413,1.5],"max":[63.997985,74.78294,4.88]} | {"boundingBoxM":{"min":[60.820401,68.378413,1.5],"max":[63.997985,74.78294,4.88]},"extentsM":[3.177584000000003,6.404527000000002,3.38],"meshSurfaceM2":165.19823143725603,"meshVolumeM3":20.170106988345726,"closedSolid":true,"windingConsistent":true,"basis":"Submalla exacta de los triángulos del modelo IFC coordinado; separación de componentes sin transformación ni retesselación."} | ["Todas las alturas parciales son hipótesis de visualización; solo la altura total de 3,38 m está acotada.","Las regiones del dibujo se usan como envolventes de cuerpos; la identificación funcional y la cota Z de cada pieza requieren verificación.","Pequeños taladros, tornillería y detalles interiores de las regiones no se extruyen como vacíos de fabricación.","La separación gráfica no aporta cotas de fabricación ni identifica piezas internas no documentadas.","Los materiales y acabados permanecen provisionales; las fotografías públicas solo orientan la apariencia."] | {"id":"AC1001C--cad-region-007","sourcePartId":"AC1001C--cad-region-007","name":"Cuerpo de equipo · región CAD 7","role":"equipment_component","classificationStatus":"provisional","classificationBasis":"Rol del subvolumen gráfico según el activo de detalle; identidad de fabricación no confirmada.","parentEquipmentId":"AC1001C","parentEquipmentGuid":"2IJ0PLLizIvfouRXAkczXf","isAssemblyIdentityCarrier":false,"sourceFaceRange":[172,200],"sourceCurrentFaceIndices":[172,173,174,175,176,177,178,179,180,181,182,183,184,185,186,187,188,189,190,191,192,193,194,195,196,197,198,199],"sourceMeshSha256":"7b60c904c9d84d22fded9be34af09a09a9c198ec8e75e61902634d5e4064c761","sourceVertexIndices":[100,101,102,103,104,105,106,107,108,109,110,111,112,113,114,115],"separationMethod":"Partición exacta de triángulos existentes; coordenadas y orientación de caras conservadas.","quantityUse":"Magnitudes geométricas del subvolumen; no son cantidades netas de material, fabricación, suministro o capacidad."} | {"id":"AC1001C","name":"Compresor de aire AC1001C","relationship":"decomposed_component","parentShapeMeaning":"La forma del objeto que conserva el ID del equipo es únicamente su componente principal; el conjunto completo requiere sus hijos."} | {"kind":"through_parent","parentEquipmentId":"AC1001C","directAnchorageVerified":false,"note":"La relación del conjunto con cimentaciones se conserva en el objeto que mantiene el ID del equipo; no se atribuye fijación directa a cada subcomponente."} | Documento de implantación y apoyo del conjunto padre; no acredita fijación individual de este componente. | AC1001C--cad-region-007 | Cuerpo de equipo · región CAD 7 | Equipos | unknown | equipment_light_gray | {"documentId":"EQ-IMPLANTACION-20260430","title":"Plano del fabricante: implantación de equipos","sheet":"LHD2609-GD01000 · espacio modelo","date":"2026-04-30","componentSourceHandles":["729DA","729DB","72A33","72A34","72A35","72A3C","72A45","72A46","72A47","72A48","72A49","72A4E","72A4F","72A50"]} | Submalla de triángulos existentes; no hay nueva posición ni nuevas caras. | Cotas globales del conjunto conservadas aparte; las dimensiones de esta ficha son de la submalla. | Coordinación del conjunto padre; anclaje directo individual no acreditado. | Superficie y volumen geométricos brutos; no constituyen cantidades netas de obra, material o fabricación. | Plano general y dimensiones globales de AC1001C; no se asignan esas dimensiones globales a este componente. | ["729DA","729DB","72A33","72A34","72A35","72A3C","72A45","72A46","72A47","72A48","72A49","72A4E","72A4F","72A50"] | 1 | no | Submalla exacta; interpretación funcional y cotas parciales provisionales.
Compresor de aire AC1001C · Cuerpo de equipo · región CAD 8 | Componente de equipo · cuerpo o accesorio | Plano del fabricante: implantación de equipos · referencia E7 | 0.400789 | 0.84881 | 0.85 | 286.65 | 287.5 | 2.32567 | 0.197716 | Apoyo relativo +0.400 m; cero absoluto provisional | Componente de equipo · cuerpo o accesorio | equipmentComponent | {"name":"No especificado","source":"Sin especificación de material en la documentación revisada","status":"unknown"} | {"documented":[{"label":"Referencia dimensional del conjunto","value":"Plano general y dimensiones globales de AC1001C; no se asignan esas dimensiones globales a este componente.","unit":"","source":"EQ-IMPLANTACION-20260430 · LHD2609-GD01000 · espacio modelo","status":"referencia_del_conjunto"}],"geometry":[{"label":"Extensión de la malla en X","value":0.40078899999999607,"unit":"m","source":"Geometría releída del IFC; datum absoluto de proceso provisional","status":"derivado"},{"label":"Extensión de la malla en Y","value":0.8488100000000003,"unit":"m","source":"Geometría releída del IFC; datum absoluto de proceso provisional","status":"derivado"},{"label":"Extensión de la malla en Z","value":0.8500000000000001,"unit":"m","source":"Geometría releída del IFC; datum absoluto de proceso provisional","status":"derivado"},{"label":"Cota inferior de visualización","value":286.65,"unit":"m","source":"Geometría releída del IFC; datum absoluto de proceso provisional","status":"derivado"},{"label":"Cota superior de visualización","value":287.5,"unit":"m","source":"Geometría releída del IFC; datum absoluto de proceso provisional","status":"derivado"}],"notes":["Las dimensiones del equipo completo se conservan en parentEquipmentDimensions.","Las extensiones en X/Y son de los ejes del modelo y no sustituyen cotas locales de fabricación.","No se infieren espesores de chapa, tolerancias ni dimensiones de piezas a partir de la partición."]} | {"documentId":"EQ-IMPLANTACION-20260430","title":"Plano del fabricante: implantación de equipos","sheet":"LHD2609-GD01000 · espacio modelo","date":"2026-04-30","componentSourceHandles":["7101E","7101F","71020","71021","71022","710E1","710E2","712F6","712F7","712F8","73403"]} | {"horizontalStatus":"derivado_del_conjunto","verticalStatus":"derivado_del_conjunto","coordinateSystem":"model_local_m","parentEquipmentId":"AC1001C","transformApplied":false,"note":"Coordenadas copiadas exactamente del equipo coordinado; no se ha movido, girado, elevado ni reescalado este componente.","foundationRelationship":"El apoyo y las cotas de instalación se documentan para el conjunto padre. Esta submalla no acredita un anclaje directo.","meshMinimumAbsoluteElevationM":286.65,"assemblyPlacementField":"parentEquipmentPositioning"} | ["Componente separado de una reconstrucción documental del conjunto. Las alturas y detalles parciales conservan las limitaciones del fabricante registradas en parentEquipmentIssues.","Esta representación exterior no crea una chapa hueca ni añade componentes internos no documentados.","La pertenencia al conjunto no demuestra apoyo o anclaje directo a la cimentación."] | {"source":{"documentId":"EQ-IMPLANTACION-20260430","title":"Plano del fabricante: implantación de equipos","sheet":"LHD2609-GD01000 · espacio modelo","date":"2026-04-30","componentSourceHandles":["7101E","7101F","71020","71021","71022","710E1","710E2","712F6","712F7","712F8","73403"]},"sourcePartId":"AC1001C--cad-region-008","sourceHandles":["7101E","7101F","71020","71021","71022","710E1","710E2","712F6","712F7","712F8","73403"],"partCount":1,"partsAreBOM":false,"status":"Submalla exacta; interpretación funcional y cotas parciales provisionales."} | {"boundingBoxM":{"min":[60.959487,69.576074,1.65],"max":[61.360276,70.424884,2.5]},"extentsM":[0.400789,0.84881,0.85],"meshSurfaceM2":2.325674,"meshVolumeM3":0.197716,"closedSolid":true,"basis":"Geometría de coordinación. Los volúmenes de referencia y subcomponentes no son cantidades de material ni componentes de fabricación certificados."} | {"documentId":"LHD2609-JG00100-20260904","title":"Cimentaciones y pedestales de equipos · revisión recibida 04/09/2026","date":"2026-09-04","sheet":"1 / 1-1","sourceHandles":["28C35","28C38","28C3B","28C89"]} | equipment | {"id":"equipment","name":"Equipos"} | {"profileId":"equipment_light_gray","name":"Equipo · gris claro provisional","materialName":"No especificado","physicalMaterialStatus":"unknown","physicalMaterialSource":"Sin especificación de material en la documentación revisada","appearanceStatus":"provisional","appearanceBasis":"Referencia visual de fotografías públicas de Jinhong Gas / fabricante. Apariencia provisional para coordinación; fotografías oficiales pueden orientar el color, pero no acreditan el material, el acabado ni el equipo concreto.","appearanceReferences":["jinhong-official-asu"],"note":"El perfil visual no confirma material, grado ni acabado del componente."} | {"status":"componente_independiente","note":"Objeto independiente seleccionable. Las caras se asignan una sola vez entre todos los componentes del conjunto.","parentEquipmentId":"AC1001C","isAssemblyIdentityCarrier":false} | {"elementId":"AC1001C--cad-region-008","ifcGuid":"0_FS5_pAfRUwDakQAzxFU1","ifcClass":"IfcBuildingElementProxy","buildingId":"process_plant","buildingName":"Planta de proceso","sourceDocumentId":"EQ-IMPLANTACION-20260430","sourceRepresentationKind":"equipmentComponent"} | {"layerId":"equipment","layerName":"Equipos","role":"Componente de equipo · cuerpo o accesorio","basis":"Clasificación por función del elemento; no modifica las especificaciones documentales."} | {"profileId":"equipment_light_gray","name":"Equipo · gris claro provisional","status":"provisional","basis":"Referencia visual de fotografías públicas de Jinhong Gas / fabricante. Apariencia provisional para coordinación; fotografías oficiales pueden orientar el color, pero no acreditan el material, el acabado ni el equipo concreto.","physicalMaterialUnchanged":true} | Equipos | No especificado | Equipos | Equipo · gris claro provisional | provisional | AC1001C--cad-region-008 | ["Componente separado de una reconstrucción documental del conjunto. Las alturas y detalles parciales conservan las limitaciones del fabricante registradas en parentEquipmentIssues.","Esta representación exterior no crea una chapa hueca ni añade componentes internos no documentados.","La pertenencia al conjunto no demuestra apoyo o anclaje directo a la cimentación."] | Geometría de coordinación. Los volúmenes de referencia y subcomponentes no son cantidades de material ni componentes de fabricación certificados. | Sin especificación de material en la documentación revisada | {"documentId":"EQ-IMPLANTACION-20260430","title":"Plano del fabricante: implantación de equipos","sheet":"LHD2609-GD01000 · espacio modelo","date":"2026-04-30","componentSourceHandles":["7101E","7101F","71020","71021","71022","710E1","710E2","712F6","712F7","712F8","73403"]} | yes | equipment_light_gray | [0.88,0.89,0.88] | 0.45 | 0.28 | Referencia visual de fotografías públicas de Jinhong Gas / fabricante. Apariencia provisional para coordinación; fotografías oficiales pueden orientar el color, pero no acreditan el material, el acabado ni el equipo concreto. | La apariencia no certifica el material físico ni el acabado de fabricación. | BIM · Equipos | AC1001C | Compresor de aire AC1001C | IfcCompressor | {"documented":[{"label":"Dimensión X local del bastidor de referencia CAD","value":2.35,"unit":"m","source":"EQ-CARGAS-20260825 · contorno CAD · handles 3F0","status":"derivado"},{"label":"Dimensión Y local del bastidor de referencia CAD","value":5.22,"unit":"m","source":"EQ-CARGAS-20260825 · contorno CAD · handles 3F0","status":"derivado"},{"label":"Altura acotada","value":3.38,"unit":"m","source":"EQ-CARGAS-20260825 · handle 25AF","status":"documentado"},{"label":"Cota relativa de la superficie de apoyo","value":0.4,"unit":"m","source":"LHD2609-JG00100-20260904 · sección 1 / 1-1 · 28C35, 28C38, 28C3B, 28C89","status":"documentado"}],"geometry":[{"label":"Extensión de la malla en X","value":3.177584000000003,"unit":"m","source":"Geometría releída del IFC; datum absoluto de proceso provisional","status":"derivado"},{"label":"Extensión de la malla en Y","value":6.404527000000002,"unit":"m","source":"Geometría releída del IFC; datum absoluto de proceso provisional","status":"derivado"},{"label":"Extensión de la malla en Z","value":3.3800000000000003,"unit":"m","source":"Geometría releída del IFC; datum absoluto de proceso provisional","status":"derivado"},{"label":"Cota inferior de visualización","value":286.5,"unit":"m","source":"Geometría releída del IFC; datum absoluto de proceso provisional","status":"derivado"},{"label":"Cota superior de visualización","value":289.88,"unit":"m","source":"Geometría releída del IFC; datum absoluto de proceso provisional","status":"derivado"}],"notes":["Las extensiones de la malla se miden en los ejes del proyecto tras el giro de implantación; no sustituyen las dimensiones locales del fabricante.","La envolvente, su volumen y los espesores de visualización no son volúmenes de material ni cantidades de compra, construcción o fabricación.","Las dimensiones documentadas distinguen cotas explícitas y medidas extraídas de contornos CAD; las dimensiones geométricas describen únicamente la malla publicada.","Las extensiones de la malla refinada y las dimensiones documentadas del contorno o bastidor tienen distinto alcance; las cotas parciales del detalle son provisionales."]} | {"Estado de la planta":"Derivado del CAD y del giro de implantación","Nivel relativo del apoyo (m)":0.4,"Estado del nivel relativo":"Documentado en el plano de cimentaciones","Cero absoluto de visualización (m)":286.1,"Estado del cero absoluto":"Provisional","Cota del apoyo de visualización (m)":286.5,"Desplazamiento aplicado a la malla (m)":0.40000000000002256,"Criterio":"Nivel de apoyo relativo documentado. Se adopta el cero de proceso a 286,10 m solo para visualización; la equivalencia absoluta no está confirmada. No se añade un espesor de montaje sin cota del fabricante."} | ["La máquina está contenida en la envolvente de la cabina acústica; su superposición no acredita una interferencia física.","El bastidor CAD coincide con la referencia de 2,35 × 5,22 m del plano de cargas, pero cuerpos y auxiliares del detalle de abril sobresalen de esa referencia, hasta aproximadamente 1,048 m por el extremo sur y 0,246 m por el lado oeste. Extensión geométrica resultante: 2,595899 × 6,268101 × 3,38 m, derivada y pendiente de coordinación entre revisiones. Permanecen dentro de la cabina acústica. Compatibilidad de revisión pendiente de fabricante.","Todas las alturas parciales son hipótesis de visualización; solo la altura total de 3,38 m está acotada.","Las regiones del dibujo se usan como envolventes de cuerpos; la identificación funcional y la cota Z de cada pieza requieren verificación.","Pequeños taladros, tornillería y detalles interiores de las regiones no se extruyen como vacíos de fabricación.","El bastidor documentado mide 2,35 × 5,22 m. Los accesorios del detalle de abril sobresalen; el conjunto refinado ocupa aproximadamente 2,596 × 6,268 m en ejes del fabricante, pendiente de coordinación entre revisiones.","El acabado de grout HA-35 de 50 mm termina en +0,400; el hormigón termina en +0,350. La losa MAC contigua termina en +0,200.","El cero absoluto de la revisión no está definido; 286,10 m sigue siendo una hipótesis de coordinación.","Se alinea el punto inferior del conjunto del equipo, incluidos los pies ya representados, con la superficie de apoyo terminada; no se añade un espesor de calzos, placa o grout del fabricante no documentado."] | {"revision":"Detalle en planta de 2026-04-30 coordinado de forma preliminar con envolventes y alturas de 2026-08-25","status":"provisional","verticalRule":"Altura total documentada: 3,38 m. Plataforma gráfica de 0,15 m; los cuerpos extraídos de la planta reciben alturas provisionales entre 1,00 y 3,38 m, detalladas por subvolumen. No se dispone de alzado acotado de cada componente.","partCount":26,"source":{"documentId":"EQ-IMPLANTACION-20260430","title":"Plano del fabricante: implantación de equipos","sheet":"LHD2609-GD01000 · espacio modelo","date":"2026-04-30"},"heightSource":{"documentId":"EQ-CARGAS-20260825","title":"Plano del fabricante: cargas de equipos","sheet":"Espacio modelo","date":"2026-08-25"},"unconfirmedDimensions":["Todas las alturas parciales son hipótesis de visualización; solo la altura total de 3,38 m está acotada.","Las regiones del dibujo se usan como envolventes de cuerpos; la identificación funcional y la cota Z de cada pieza requieren verificación.","Pequeños taladros, tornillería y detalles interiores de las regiones no se extruyen como vacíos de fabricación."],"quantityUse":"Magnitudes de la geometría representada; no son cantidades de material, obra, compra, capacidad útil ni fabricación. En geometrías compuestas se suman superficies y volúmenes de partes y pueden existir solapes no depurados.","partsAreBOM":false} | equipment_component | {"min":[60.820401,68.378413,1.5],"max":[63.997985,74.78294,4.88]} | {"boundingBoxM":{"min":[60.820401,68.378413,1.5],"max":[63.997985,74.78294,4.88]},"extentsM":[3.177584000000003,6.404527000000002,3.38],"meshSurfaceM2":165.19823143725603,"meshVolumeM3":20.170106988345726,"closedSolid":true,"windingConsistent":true,"basis":"Submalla exacta de los triángulos del modelo IFC coordinado; separación de componentes sin transformación ni retesselación."} | ["Todas las alturas parciales son hipótesis de visualización; solo la altura total de 3,38 m está acotada.","Las regiones del dibujo se usan como envolventes de cuerpos; la identificación funcional y la cota Z de cada pieza requieren verificación.","Pequeños taladros, tornillería y detalles interiores de las regiones no se extruyen como vacíos de fabricación.","La separación gráfica no aporta cotas de fabricación ni identifica piezas internas no documentadas.","Los materiales y acabados permanecen provisionales; las fotografías públicas solo orientan la apariencia."] | {"id":"AC1001C--cad-region-008","sourcePartId":"AC1001C--cad-region-008","name":"Cuerpo de equipo · región CAD 8","role":"equipment_component","classificationStatus":"provisional","classificationBasis":"Rol del subvolumen gráfico según el activo de detalle; identidad de fabricación no confirmada.","parentEquipmentId":"AC1001C","parentEquipmentGuid":"2IJ0PLLizIvfouRXAkczXf","isAssemblyIdentityCarrier":false,"sourceFaceRange":[200,256],"sourceCurrentFaceIndices":[200,201,202,203,204,205,206,207,208,209,210,211,212,213,214,215,216,217,218,219,220,221,222,223,224,225,226,227,228,229,230,231,232,233,234,235,236,237,238,239,240,241,242,243,244,245,246,247,248,249,250,251,252,253,254,255],"sourceMeshSha256":"7b60c904c9d84d22fded9be34af09a09a9c198ec8e75e61902634d5e4064c761","sourceVertexIndices":[116,117,118,119,120,121,122,123,124,125,126,127,128,129,130,131,132,133,134,135,136,137,138,139,140,141,142,143,144,145],"separationMethod":"Partición exacta de triángulos existentes; coordenadas y orientación de caras conservadas.","quantityUse":"Magnitudes geométricas del subvolumen; no son cantidades netas de material, fabricación, suministro o capacidad."} | {"id":"AC1001C","name":"Compresor de aire AC1001C","relationship":"decomposed_component","parentShapeMeaning":"La forma del objeto que conserva el ID del equipo es únicamente su componente principal; el conjunto completo requiere sus hijos."} | {"kind":"through_parent","parentEquipmentId":"AC1001C","directAnchorageVerified":false,"note":"La relación del conjunto con cimentaciones se conserva en el objeto que mantiene el ID del equipo; no se atribuye fijación directa a cada subcomponente."} | Documento de implantación y apoyo del conjunto padre; no acredita fijación individual de este componente. | AC1001C--cad-region-008 | Cuerpo de equipo · región CAD 8 | Equipos | unknown | equipment_light_gray | {"documentId":"EQ-IMPLANTACION-20260430","title":"Plano del fabricante: implantación de equipos","sheet":"LHD2609-GD01000 · espacio modelo","date":"2026-04-30","componentSourceHandles":["7101E","7101F","71020","71021","71022","710E1","710E2","712F6","712F7","712F8","73403"]} | Submalla de triángulos existentes; no hay nueva posición ni nuevas caras. | Cotas globales del conjunto conservadas aparte; las dimensiones de esta ficha son de la submalla. | Coordinación del conjunto padre; anclaje directo individual no acreditado. | Superficie y volumen geométricos brutos; no constituyen cantidades netas de obra, material o fabricación. | Plano general y dimensiones globales de AC1001C; no se asignan esas dimensiones globales a este componente. | ["7101E","7101F","71020","71021","71022","710E1","710E2","712F6","712F7","712F8","73403"] | 1 | no | Submalla exacta; interpretación funcional y cotas parciales provisionales.
Compresor de aire AC1001C · Cuerpo de equipo · región CAD 9 | Componente de equipo · cuerpo o accesorio | Plano del fabricante: implantación de equipos · referencia E7 | 0.414956 | 0.64071 | 1.5 | 286.65 | 288.15 | 3.2143 | 0.302922 | Apoyo relativo +0.400 m; cero absoluto provisional | Componente de equipo · cuerpo o accesorio | equipmentComponent | {"name":"No especificado","source":"Sin especificación de material en la documentación revisada","status":"unknown"} | {"documented":[{"label":"Referencia dimensional del conjunto","value":"Plano general y dimensiones globales de AC1001C; no se asignan esas dimensiones globales a este componente.","unit":"","source":"EQ-IMPLANTACION-20260430 · LHD2609-GD01000 · espacio modelo","status":"referencia_del_conjunto"}],"geometry":[{"label":"Extensión de la malla en X","value":0.41495600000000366,"unit":"m","source":"Geometría releída del IFC; datum absoluto de proceso provisional","status":"derivado"},{"label":"Extensión de la malla en Y","value":0.6407099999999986,"unit":"m","source":"Geometría releída del IFC; datum absoluto de proceso provisional","status":"derivado"},{"label":"Extensión de la malla en Z","value":1.5,"unit":"m","source":"Geometría releída del IFC; datum absoluto de proceso provisional","status":"derivado"},{"label":"Cota inferior de visualización","value":286.65,"unit":"m","source":"Geometría releída del IFC; datum absoluto de proceso provisional","status":"derivado"},{"label":"Cota superior de visualización","value":288.15,"unit":"m","source":"Geometría releída del IFC; datum absoluto de proceso provisional","status":"derivado"}],"notes":["Las dimensiones del equipo completo se conservan en parentEquipmentDimensions.","Las extensiones en X/Y son de los ejes del modelo y no sustituyen cotas locales de fabricación.","No se infieren espesores de chapa, tolerancias ni dimensiones de piezas a partir de la partición."]} | {"documentId":"EQ-IMPLANTACION-20260430","title":"Plano del fabricante: implantación de equipos","sheet":"LHD2609-GD01000 · espacio modelo","date":"2026-04-30","componentSourceHandles":["72546","72549","725A4","725A5","725A7","72763","7276F","72777","72789","72794","727AC","727AE","727AF","727B0","727B1","727B2","733F4","733F5","733F6","733FB","733FC","733FD"]} | {"horizontalStatus":"derivado_del_conjunto","verticalStatus":"derivado_del_conjunto","coordinateSystem":"model_local_m","parentEquipmentId":"AC1001C","transformApplied":false,"note":"Coordenadas copiadas exactamente del equipo coordinado; no se ha movido, girado, elevado ni reescalado este componente.","foundationRelationship":"El apoyo y las cotas de instalación se documentan para el conjunto padre. Esta submalla no acredita un anclaje directo.","meshMinimumAbsoluteElevationM":286.65,"assemblyPlacementField":"parentEquipmentPositioning"} | ["Componente separado de una reconstrucción documental del conjunto. Las alturas y detalles parciales conservan las limitaciones del fabricante registradas en parentEquipmentIssues.","Esta representación exterior no crea una chapa hueca ni añade componentes internos no documentados.","La pertenencia al conjunto no demuestra apoyo o anclaje directo a la cimentación."] | {"source":{"documentId":"EQ-IMPLANTACION-20260430","title":"Plano del fabricante: implantación de equipos","sheet":"LHD2609-GD01000 · espacio modelo","date":"2026-04-30","componentSourceHandles":["72546","72549","725A4","725A5","725A7","72763","7276F","72777","72789","72794","727AC","727AE","727AF","727B0","727B1","727B2","733F4","733F5","733F6","733FB","733FC","733FD"]},"sourcePartId":"AC1001C--cad-region-009","sourceHandles":["72546","72549","725A4","725A5","725A7","72763","7276F","72777","72789","72794","727AC","727AE","727AF","727B0","727B1","727B2","733F4","733F5","733F6","733FB","733FC","733FD"],"partCount":1,"partsAreBOM":false,"status":"Submalla exacta; interpretación funcional y cotas parciales provisionales."} | {"boundingBoxM":{"min":[63.033567,70.72016,1.65],"max":[63.448523,71.36087,3.15]},"extentsM":[0.414956,0.64071,1.5],"meshSurfaceM2":3.214297,"meshVolumeM3":0.302922,"closedSolid":true,"basis":"Geometría de coordinación. Los volúmenes de referencia y subcomponentes no son cantidades de material ni componentes de fabricación certificados."} | {"documentId":"LHD2609-JG00100-20260904","title":"Cimentaciones y pedestales de equipos · revisión recibida 04/09/2026","date":"2026-09-04","sheet":"1 / 1-1","sourceHandles":["28C35","28C38","28C3B","28C89"]} | equipment | {"id":"equipment","name":"Equipos"} | {"profileId":"equipment_light_gray","name":"Equipo · gris claro provisional","materialName":"No especificado","physicalMaterialStatus":"unknown","physicalMaterialSource":"Sin especificación de material en la documentación revisada","appearanceStatus":"provisional","appearanceBasis":"Referencia visual de fotografías públicas de Jinhong Gas / fabricante. Apariencia provisional para coordinación; fotografías oficiales pueden orientar el color, pero no acreditan el material, el acabado ni el equipo concreto.","appearanceReferences":["jinhong-official-asu"],"note":"El perfil visual no confirma material, grado ni acabado del componente."} | {"status":"componente_independiente","note":"Objeto independiente seleccionable. Las caras se asignan una sola vez entre todos los componentes del conjunto.","parentEquipmentId":"AC1001C","isAssemblyIdentityCarrier":false} | {"elementId":"AC1001C--cad-region-009","ifcGuid":"3iQ_HYgvTGrRANbghUjHkG","ifcClass":"IfcBuildingElementProxy","buildingId":"process_plant","buildingName":"Planta de proceso","sourceDocumentId":"EQ-IMPLANTACION-20260430","sourceRepresentationKind":"equipmentComponent"} | {"layerId":"equipment","layerName":"Equipos","role":"Componente de equipo · cuerpo o accesorio","basis":"Clasificación por función del elemento; no modifica las especificaciones documentales."} | {"profileId":"equipment_light_gray","name":"Equipo · gris claro provisional","status":"provisional","basis":"Referencia visual de fotografías públicas de Jinhong Gas / fabricante. Apariencia provisional para coordinación; fotografías oficiales pueden orientar el color, pero no acreditan el material, el acabado ni el equipo concreto.","physicalMaterialUnchanged":true} | Equipos | No especificado | Equipos | Equipo · gris claro provisional | provisional | AC1001C--cad-region-009 | ["Componente separado de una reconstrucción documental del conjunto. Las alturas y detalles parciales conservan las limitaciones del fabricante registradas en parentEquipmentIssues.","Esta representación exterior no crea una chapa hueca ni añade componentes internos no documentados.","La pertenencia al conjunto no demuestra apoyo o anclaje directo a la cimentación."] | Geometría de coordinación. Los volúmenes de referencia y subcomponentes no son cantidades de material ni componentes de fabricación certificados. | Sin especificación de material en la documentación revisada | {"documentId":"EQ-IMPLANTACION-20260430","title":"Plano del fabricante: implantación de equipos","sheet":"LHD2609-GD01000 · espacio modelo","date":"2026-04-30","componentSourceHandles":["72546","72549","725A4","725A5","725A7","72763","7276F","72777","72789","72794","727AC","727AE","727AF","727B0","727B1","727B2","733F4","733F5","733F6","733FB","733FC","733FD"]} | yes | equipment_light_gray | [0.88,0.89,0.88] | 0.45 | 0.28 | Referencia visual de fotografías públicas de Jinhong Gas / fabricante. Apariencia provisional para coordinación; fotografías oficiales pueden orientar el color, pero no acreditan el material, el acabado ni el equipo concreto. | La apariencia no certifica el material físico ni el acabado de fabricación. | BIM · Equipos | AC1001C | Compresor de aire AC1001C | IfcCompressor | {"documented":[{"label":"Dimensión X local del bastidor de referencia CAD","value":2.35,"unit":"m","source":"EQ-CARGAS-20260825 · contorno CAD · handles 3F0","status":"derivado"},{"label":"Dimensión Y local del bastidor de referencia CAD","value":5.22,"unit":"m","source":"EQ-CARGAS-20260825 · contorno CAD · handles 3F0","status":"derivado"},{"label":"Altura acotada","value":3.38,"unit":"m","source":"EQ-CARGAS-20260825 · handle 25AF","status":"documentado"},{"label":"Cota relativa de la superficie de apoyo","value":0.4,"unit":"m","source":"LHD2609-JG00100-20260904 · sección 1 / 1-1 · 28C35, 28C38, 28C3B, 28C89","status":"documentado"}],"geometry":[{"label":"Extensión de la malla en X","value":3.177584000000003,"unit":"m","source":"Geometría releída del IFC; datum absoluto de proceso provisional","status":"derivado"},{"label":"Extensión de la malla en Y","value":6.404527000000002,"unit":"m","source":"Geometría releída del IFC; datum absoluto de proceso provisional","status":"derivado"},{"label":"Extensión de la malla en Z","value":3.3800000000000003,"unit":"m","source":"Geometría releída del IFC; datum absoluto de proceso provisional","status":"derivado"},{"label":"Cota inferior de visualización","value":286.5,"unit":"m","source":"Geometría releída del IFC; datum absoluto de proceso provisional","status":"derivado"},{"label":"Cota superior de visualización","value":289.88,"unit":"m","source":"Geometría releída del IFC; datum absoluto de proceso provisional","status":"derivado"}],"notes":["Las extensiones de la malla se miden en los ejes del proyecto tras el giro de implantación; no sustituyen las dimensiones locales del fabricante.","La envolvente, su volumen y los espesores de visualización no son volúmenes de material ni cantidades de compra, construcción o fabricación.","Las dimensiones documentadas distinguen cotas explícitas y medidas extraídas de contornos CAD; las dimensiones geométricas describen únicamente la malla publicada.","Las extensiones de la malla refinada y las dimensiones documentadas del contorno o bastidor tienen distinto alcance; las cotas parciales del detalle son provisionales."]} | {"Estado de la planta":"Derivado del CAD y del giro de implantación","Nivel relativo del apoyo (m)":0.4,"Estado del nivel relativo":"Documentado en el plano de cimentaciones","Cero absoluto de visualización (m)":286.1,"Estado del cero absoluto":"Provisional","Cota del apoyo de visualización (m)":286.5,"Desplazamiento aplicado a la malla (m)":0.40000000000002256,"Criterio":"Nivel de apoyo relativo documentado. Se adopta el cero de proceso a 286,10 m solo para visualización; la equivalencia absoluta no está confirmada. No se añade un espesor de montaje sin cota del fabricante."} | ["La máquina está contenida en la envolvente de la cabina acústica; su superposición no acredita una interferencia física.","El bastidor CAD coincide con la referencia de 2,35 × 5,22 m del plano de cargas, pero cuerpos y auxiliares del detalle de abril sobresalen de esa referencia, hasta aproximadamente 1,048 m por el extremo sur y 0,246 m por el lado oeste. Extensión geométrica resultante: 2,595899 × 6,268101 × 3,38 m, derivada y pendiente de coordinación entre revisiones. Permanecen dentro de la cabina acústica. Compatibilidad de revisión pendiente de fabricante.","Todas las alturas parciales son hipótesis de visualización; solo la altura total de 3,38 m está acotada.","Las regiones del dibujo se usan como envolventes de cuerpos; la identificación funcional y la cota Z de cada pieza requieren verificación.","Pequeños taladros, tornillería y detalles interiores de las regiones no se extruyen como vacíos de fabricación.","El bastidor documentado mide 2,35 × 5,22 m. Los accesorios del detalle de abril sobresalen; el conjunto refinado ocupa aproximadamente 2,596 × 6,268 m en ejes del fabricante, pendiente de coordinación entre revisiones.","El acabado de grout HA-35 de 50 mm termina en +0,400; el hormigón termina en +0,350. La losa MAC contigua termina en +0,200.","El cero absoluto de la revisión no está definido; 286,10 m sigue siendo una hipótesis de coordinación.","Se alinea el punto inferior del conjunto del equipo, incluidos los pies ya representados, con la superficie de apoyo terminada; no se añade un espesor de calzos, placa o grout del fabricante no documentado."] | {"revision":"Detalle en planta de 2026-04-30 coordinado de forma preliminar con envolventes y alturas de 2026-08-25","status":"provisional","verticalRule":"Altura total documentada: 3,38 m. Plataforma gráfica de 0,15 m; los cuerpos extraídos de la planta reciben alturas provisionales entre 1,00 y 3,38 m, detalladas por subvolumen. No se dispone de alzado acotado de cada componente.","partCount":26,"source":{"documentId":"EQ-IMPLANTACION-20260430","title":"Plano del fabricante: implantación de equipos","sheet":"LHD2609-GD01000 · espacio modelo","date":"2026-04-30"},"heightSource":{"documentId":"EQ-CARGAS-20260825","title":"Plano del fabricante: cargas de equipos","sheet":"Espacio modelo","date":"2026-08-25"},"unconfirmedDimensions":["Todas las alturas parciales son hipótesis de visualización; solo la altura total de 3,38 m está acotada.","Las regiones del dibujo se usan como envolventes de cuerpos; la identificación funcional y la cota Z de cada pieza requieren verificación.","Pequeños taladros, tornillería y detalles interiores de las regiones no se extruyen como vacíos de fabricación."],"quantityUse":"Magnitudes de la geometría representada; no son cantidades de material, obra, compra, capacidad útil ni fabricación. En geometrías compuestas se suman superficies y volúmenes de partes y pueden existir solapes no depurados.","partsAreBOM":false} | equipment_component | {"min":[60.820401,68.378413,1.5],"max":[63.997985,74.78294,4.88]} | {"boundingBoxM":{"min":[60.820401,68.378413,1.5],"max":[63.997985,74.78294,4.88]},"extentsM":[3.177584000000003,6.404527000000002,3.38],"meshSurfaceM2":165.19823143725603,"meshVolumeM3":20.170106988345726,"closedSolid":true,"windingConsistent":true,"basis":"Submalla exacta de los triángulos del modelo IFC coordinado; separación de componentes sin transformación ni retesselación."} | ["Todas las alturas parciales son hipótesis de visualización; solo la altura total de 3,38 m está acotada.","Las regiones del dibujo se usan como envolventes de cuerpos; la identificación funcional y la cota Z de cada pieza requieren verificación.","Pequeños taladros, tornillería y detalles interiores de las regiones no se extruyen como vacíos de fabricación.","La separación gráfica no aporta cotas de fabricación ni identifica piezas internas no documentadas.","Los materiales y acabados permanecen provisionales; las fotografías públicas solo orientan la apariencia."] | {"id":"AC1001C--cad-region-009","sourcePartId":"AC1001C--cad-region-009","name":"Cuerpo de equipo · región CAD 9","role":"equipment_component","classificationStatus":"provisional","classificationBasis":"Rol del subvolumen gráfico según el activo de detalle; identidad de fabricación no confirmada.","parentEquipmentId":"AC1001C","parentEquipmentGuid":"2IJ0PLLizIvfouRXAkczXf","isAssemblyIdentityCarrier":false,"sourceFaceRange":[256,268],"sourceCurrentFaceIndices":[256,257,258,259,260,261,262,263,264,265,266,267],"sourceMeshSha256":"7b60c904c9d84d22fded9be34af09a09a9c198ec8e75e61902634d5e4064c761","sourceVertexIndices":[146,147,148,149,150,151,152,153],"separationMethod":"Partición exacta de triángulos existentes; coordenadas y orientación de caras conservadas.","quantityUse":"Magnitudes geométricas del subvolumen; no son cantidades netas de material, fabricación, suministro o capacidad."} | {"id":"AC1001C","name":"Compresor de aire AC1001C","relationship":"decomposed_component","parentShapeMeaning":"La forma del objeto que conserva el ID del equipo es únicamente su componente principal; el conjunto completo requiere sus hijos."} | {"kind":"through_parent","parentEquipmentId":"AC1001C","directAnchorageVerified":false,"note":"La relación del conjunto con cimentaciones se conserva en el objeto que mantiene el ID del equipo; no se atribuye fijación directa a cada subcomponente."} | Documento de implantación y apoyo del conjunto padre; no acredita fijación individual de este componente. | AC1001C--cad-region-009 | Cuerpo de equipo · región CAD 9 | Equipos | unknown | equipment_light_gray | {"documentId":"EQ-IMPLANTACION-20260430","title":"Plano del fabricante: implantación de equipos","sheet":"LHD2609-GD01000 · espacio modelo","date":"2026-04-30","componentSourceHandles":["72546","72549","725A4","725A5","725A7","72763","7276F","72777","72789","72794","727AC","727AE","727AF","727B0","727B1","727B2","733F4","733F5","733F6","733FB","733FC","733FD"]} | Submalla de triángulos existentes; no hay nueva posición ni nuevas caras. | Cotas globales del conjunto conservadas aparte; las dimensiones de esta ficha son de la submalla. | Coordinación del conjunto padre; anclaje directo individual no acreditado. | Superficie y volumen geométricos brutos; no constituyen cantidades netas de obra, material o fabricación. | Plano general y dimensiones globales de AC1001C; no se asignan esas dimensiones globales a este componente. | ["72546","72549","725A4","725A5","725A7","72763","7276F","72777","72789","72794","727AC","727AE","727AF","727B0","727B1","727B2","733F4","733F5","733F6","733FB","733FC","733FD"] | 1 | no | Submalla exacta; interpretación funcional y cotas parciales provisionales.
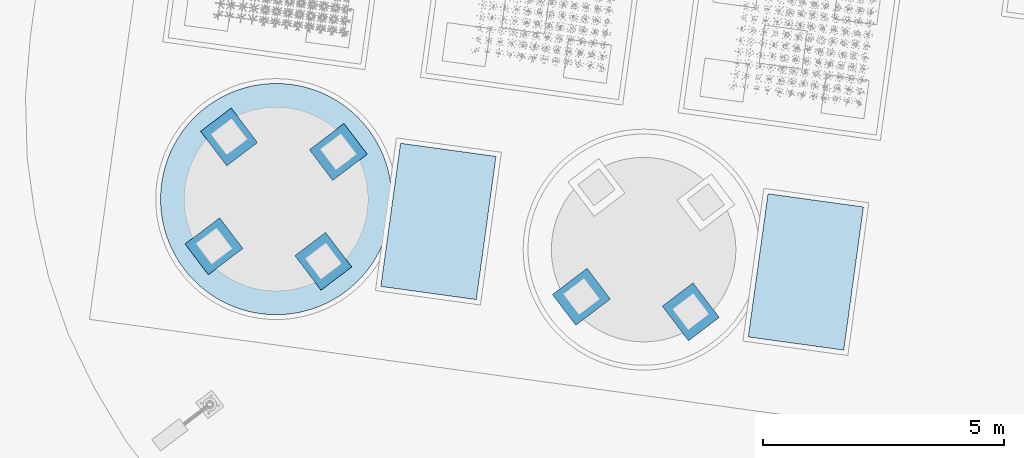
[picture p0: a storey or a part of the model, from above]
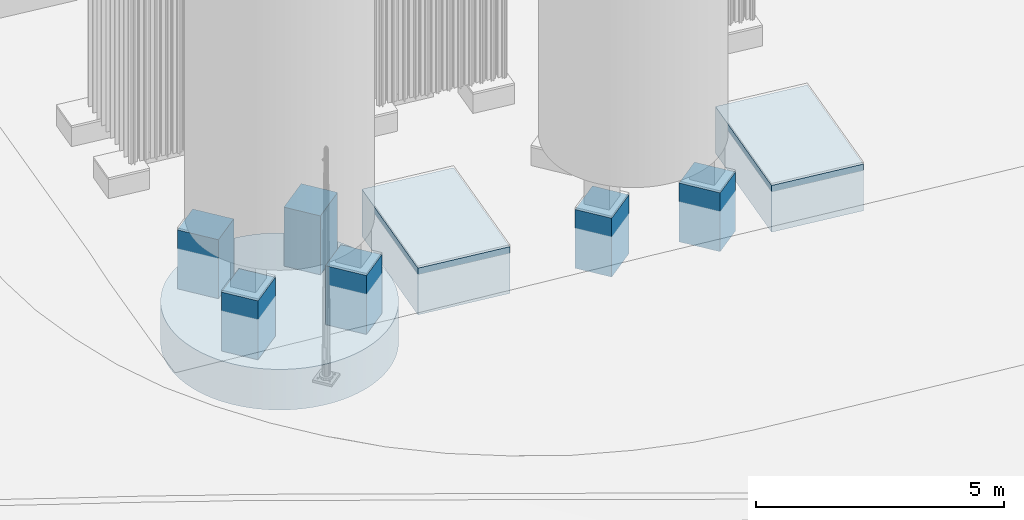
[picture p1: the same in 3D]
Properties of the parts of a building model (IFC4), part 46 of 134

# IfcBuildingElementProxy (140)
Name | Description | Document | Extensión de la malla en X (m) = ExtensionX (m) | Extensión de la malla en Y (m) = ExtensionY (m) | Extensión de la malla en Z (m) = ExtensionZ (m) | Cota inferior de visualización (m) | Cota superior de visualización (m) | SuperficieDeLaMalla (m2) | VolumenGeometrico (m3) | level | category = Categoria = Funcion | representationKind | material | dimensions | JH_InformacionBIM, source = DocumentoFuente | positioning = PosicionYEstado | issues | detailGeometry | geometryMetrics | installationSource | layerId = IdentificadorCapa | visualLayer | materialAppearance | componentSeparation | visualizationIdentity | classification | appearance | Disciplina | Material | Capa BIM = NombreCapa | Acabado de visualización = Acabado | Estado del acabado = Estado | Identificador | JH_Trazabilidad, IncidenciasPendientes | UsoDeLasMagnitudes | JH_EvidenciaDeMaterial, source | JH_DetalleGeometrico, source | VisibilidadInicial | Perfil | ColorRGB | Rugosidad | Metallicidad | Referencia | Nota | Group | parentEquipmentId = Identificador del equipo padre | parentEquipmentName = Equipo padre | parentEquipmentIfcClass | parentEquipmentDimensions | parentEquipmentPositioning | parentEquipmentIssues | parentEquipmentDetail | componentRole = Rol del componente | assemblyBBox | assemblyGeometryMetrics | manufacturerDetailsPending | component | assembly | foundationRelationship | installationSourceScope | Identificador del elemento = sourcePartId | Componente | Capa de visualización | Estado del material | Perfil visual del material | Fuente del componente | Criterio de partición | Criterio de las dimensiones | Relación con cimentaciones | Aplicabilidad de las mediciones | Referencia dimensional del conjunto | sourceHandles | partCount | partsAreBOM | status
Compresor de aire AC1001C · Cuerpo de equipo · región CAD 14 | Componente de equipo · cuerpo o accesorio | Plano del fabricante: implantación de equipos · referencia E7 | 0.211632 | 0.578076 | 1.9 | 286.65 | 288.55 | 3.97144 | 0.126298 | Apoyo relativo +0.400 m; cero absoluto provisional | Componente de equipo · cuerpo o accesorio | equipmentComponent | {"name":"No especificado","source":"Sin especificación de material en la documentación revisada","status":"unknown"} | {"documented":[{"label":"Referencia dimensional del conjunto","value":"Plano general y dimensiones globales de AC1001C; no se asignan esas dimensiones globales a este componente.","unit":"","source":"EQ-IMPLANTACION-20260430 · LHD2609-GD01000 · espacio modelo","status":"referencia_del_conjunto"}],"geometry":[{"label":"Extensión de la malla en X","value":0.2116320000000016,"unit":"m","source":"Geometría releída del IFC; datum absoluto de proceso provisional","status":"derivado"},{"label":"Extensión de la malla en Y","value":0.57807600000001,"unit":"m","source":"Geometría releída del IFC; datum absoluto de proceso provisional","status":"derivado"},{"label":"Extensión de la malla en Z","value":1.9,"unit":"m","source":"Geometría releída del IFC; datum absoluto de proceso provisional","status":"derivado"},{"label":"Cota inferior de visualización","value":286.65,"unit":"m","source":"Geometría releída del IFC; datum absoluto de proceso provisional","status":"derivado"},{"label":"Cota superior de visualización","value":288.55,"unit":"m","source":"Geometría releída del IFC; datum absoluto de proceso provisional","status":"derivado"}],"notes":["Las dimensiones del equipo completo se conservan en parentEquipmentDimensions.","Las extensiones en X/Y son de los ejes del modelo y no sustituyen cotas locales de fabricación.","No se infieren espesores de chapa, tolerancias ni dimensiones de piezas a partir de la partición."]} | {"documentId":"EQ-IMPLANTACION-20260430","title":"Plano del fabricante: implantación de equipos","sheet":"LHD2609-GD01000 · espacio modelo","date":"2026-04-30","componentSourceHandles":["71428","71618","7189D","7189E","718A2","718A4","718A7","71930","71931","7193B","7193D","72411","7241B","7241C","7241D","72420","72422","72423","72424","72513","729B9","729BB","729BC","72F28","72F2F","72F39","72F3E","72F40","72F54","72F5B","72F5F","72F60","72F63","72F69","72F70","72F73","72F75","72F78","72F79","72F7A","72F7D","72F80","72F84","72F86","72F88","72F89","72F8A","72F8B","72F8C","72F8D","72F8E","72F8F","72F90","72F92","72F9B","72F9D","72F9E","72FB1","72FB2","72FB6","72FB8","72FC0","72FC2","72FCB","72FCD","72FD6","72FD7","72FD8","72FD9","72FDA","72FDB","72FDC","72FDE","72FEC","72FED","72FEE","72FEF","72FF0","72FF1","72FF2","72FF3","72FF4","72FF5","72FF6","72FF7","72FFA","72FFB","72FFC","72FFE","72FFF","73000","73001","73004","73005","73008","73009","7300A","7300B","7300E","7300F","73010","73012","73013","73014","73015","73018","73019","7301C","7301D","7301E","7301F","73022","73023","73024","7302A","7302B","7302C","7302D","73030","73035","73036","7303A","7303C","7303D","7303E","7303F","73040","73041","73042","73047","73048","73049","7304B","7304C","73058","7305C","7305D","7305E","73062","73066","73067","73068","73069","7306A","7306C","7306D","7306F","73070","73071","73072","73073","73074","730A9","730AB","730AC","730AD","730AE","730AF","730B0","730B1","730B2","730B3","730B4","730B5","730B8","730BC","730BD","730BE","730BF","730C0","730C1","730C2","730C3","730C4","730C5","730C7","730C9","730CB","730CC","730CD","730CF","730D2","730D5","730D8","730D9","730DA","730DC","730DF","730E2","730E8","730EB","730EF","730F0","730F1","730F4","730F6","730F7","730F8","730FA","7310B","732E7"]} | {"horizontalStatus":"derivado_del_conjunto","verticalStatus":"derivado_del_conjunto","coordinateSystem":"model_local_m","parentEquipmentId":"AC1001C","transformApplied":false,"note":"Coordenadas copiadas exactamente del equipo coordinado; no se ha movido, girado, elevado ni reescalado este componente.","foundationRelationship":"El apoyo y las cotas de instalación se documentan para el conjunto padre. Esta submalla no acredita un anclaje directo.","meshMinimumAbsoluteElevationM":286.65,"assemblyPlacementField":"parentEquipmentPositioning"} | ["Componente separado de una reconstrucción documental del conjunto. Las alturas y detalles parciales conservan las limitaciones del fabricante registradas en parentEquipmentIssues.","Esta representación exterior no crea una chapa hueca ni añade componentes internos no documentados.","La pertenencia al conjunto no demuestra apoyo o anclaje directo a la cimentación."] | {"source":{"documentId":"EQ-IMPLANTACION-20260430","title":"Plano del fabricante: implantación de equipos","sheet":"LHD2609-GD01000 · espacio modelo","date":"2026-04-30","componentSourceHandles":["71428","71618","7189D","7189E","718A2","718A4","718A7","71930","71931","7193B","7193D","72411","7241B","7241C","7241D","72420","72422","72423","72424","72513","729B9","729BB","729BC","72F28","72F2F","72F39","72F3E","72F40","72F54","72F5B","72F5F","72F60","72F63","72F69","72F70","72F73","72F75","72F78","72F79","72F7A","72F7D","72F80","72F84","72F86","72F88","72F89","72F8A","72F8B","72F8C","72F8D","72F8E","72F8F","72F90","72F92","72F9B","72F9D","72F9E","72FB1","72FB2","72FB6","72FB8","72FC0","72FC2","72FCB","72FCD","72FD6","72FD7","72FD8","72FD9","72FDA","72FDB","72FDC","72FDE","72FEC","72FED","72FEE","72FEF","72FF0","72FF1","72FF2","72FF3","72FF4","72FF5","72FF6","72FF7","72FFA","72FFB","72FFC","72FFE","72FFF","73000","73001","73004","73005","73008","73009","7300A","7300B","7300E","7300F","73010","73012","73013","73014","73015","73018","73019","7301C","7301D","7301E","7301F","73022","73023","73024","7302A","7302B","7302C","7302D","73030","73035","73036","7303A","7303C","7303D","7303E","7303F","73040","73041","73042","73047","73048","73049","7304B","7304C","73058","7305C","7305D","7305E","73062","73066","73067","73068","73069","7306A","7306C","7306D","7306F","73070","73071","73072","73073","73074","730A9","730AB","730AC","730AD","730AE","730AF","730B0","730B1","730B2","730B3","730B4","730B5","730B8","730BC","730BD","730BE","730BF","730C0","730C1","730C2","730C3","730C4","730C5","730C7","730C9","730CB","730CC","730CD","730CF","730D2","730D5","730D8","730D9","730DA","730DC","730DF","730E2","730E8","730EB","730EF","730F0","730F1","730F4","730F6","730F7","730F8","730FA","7310B","732E7"]},"sourcePartId":"AC1001C--cad-region-014","sourceHandles":["71428","71618","7189D","7189E","718A2","718A4","718A7","71930","71931","7193B","7193D","72411","7241B","7241C","7241D","72420","72422","72423","72424","72513","729B9","729BB","729BC","72F28","72F2F","72F39","72F3E","72F40","72F54","72F5B","72F5F","72F60","72F63","72F69","72F70","72F73","72F75","72F78","72F79","72F7A","72F7D","72F80","72F84","72F86","72F88","72F89","72F8A","72F8B","72F8C","72F8D","72F8E","72F8F","72F90","72F92","72F9B","72F9D","72F9E","72FB1","72FB2","72FB6","72FB8","72FC0","72FC2","72FCB","72FCD","72FD6","72FD7","72FD8","72FD9","72FDA","72FDB","72FDC","72FDE","72FEC","72FED","72FEE","72FEF","72FF0","72FF1","72FF2","72FF3","72FF4","72FF5","72FF6","72FF7","72FFA","72FFB","72FFC","72FFE","72FFF","73000","73001","73004","73005","73008","73009","7300A","7300B","7300E","7300F","73010","73012","73013","73014","73015","73018","73019","7301C","7301D","7301E","7301F","73022","73023","73024","7302A","7302B","7302C","7302D","73030","73035","73036","7303A","7303C","7303D","7303E","7303F","73040","73041","73042","73047","73048","73049","7304B","7304C","73058","7305C","7305D","7305E","73062","73066","73067","73068","73069","7306A","7306C","7306D","7306F","73070","73071","73072","73073","73074","730A9","730AB","730AC","730AD","730AE","730AF","730B0","730B1","730B2","730B3","730B4","730B5","730B8","730BC","730BD","730BE","730BF","730C0","730C1","730C2","730C3","730C4","730C5","730C7","730C9","730CB","730CC","730CD","730CF","730D2","730D5","730D8","730D9","730DA","730DC","730DF","730E2","730E8","730EB","730EF","730F0","730F1","730F4","730F6","730F7","730F8","730FA","7310B","732E7"],"partCount":1,"partsAreBOM":false,"status":"Submalla exacta; interpretación funcional y cotas parciales provisionales."} | {"boundingBoxM":{"min":[62.117168,71.854227,1.65],"max":[62.3288,72.432303,3.55]},"extentsM":[0.211632,0.578076,1.9],"meshSurfaceM2":3.971437,"meshVolumeM3":0.126298,"closedSolid":true,"basis":"Geometría de coordinación. Los volúmenes de referencia y subcomponentes no son cantidades de material ni componentes de fabricación certificados."} | {"documentId":"LHD2609-JG00100-20260904","title":"Cimentaciones y pedestales de equipos · revisión recibida 04/09/2026","date":"2026-09-04","sheet":"1 / 1-1","sourceHandles":["28C35","28C38","28C3B","28C89"]} | equipment | {"id":"equipment","name":"Equipos"} | {"profileId":"equipment_light_gray","name":"Equipo · gris claro provisional","materialName":"No especificado","physicalMaterialStatus":"unknown","physicalMaterialSource":"Sin especificación de material en la documentación revisada","appearanceStatus":"provisional","appearanceBasis":"Referencia visual de fotografías públicas de Jinhong Gas / fabricante. Apariencia provisional para coordinación; fotografías oficiales pueden orientar el color, pero no acreditan el material, el acabado ni el equipo concreto.","appearanceReferences":["jinhong-official-asu"],"note":"El perfil visual no confirma material, grado ni acabado del componente."} | {"status":"componente_independiente","note":"Objeto independiente seleccionable. Las caras se asignan una sola vez entre todos los componentes del conjunto.","parentEquipmentId":"AC1001C","isAssemblyIdentityCarrier":false} | {"elementId":"AC1001C--cad-region-014","ifcGuid":"2I$mUHHsfHEQZs6arrRRRJ","ifcClass":"IfcBuildingElementProxy","buildingId":"process_plant","buildingName":"Planta de proceso","sourceDocumentId":"EQ-IMPLANTACION-20260430","sourceRepresentationKind":"equipmentComponent"} | {"layerId":"equipment","layerName":"Equipos","role":"Componente de equipo · cuerpo o accesorio","basis":"Clasificación por función del elemento; no modifica las especificaciones documentales."} | {"profileId":"equipment_light_gray","name":"Equipo · gris claro provisional","status":"provisional","basis":"Referencia visual de fotografías públicas de Jinhong Gas / fabricante. Apariencia provisional para coordinación; fotografías oficiales pueden orientar el color, pero no acreditan el material, el acabado ni el equipo concreto.","physicalMaterialUnchanged":true} | Equipos | No especificado | Equipos | Equipo · gris claro provisional | provisional | AC1001C--cad-region-014 | ["Componente separado de una reconstrucción documental del conjunto. Las alturas y detalles parciales conservan las limitaciones del fabricante registradas en parentEquipmentIssues.","Esta representación exterior no crea una chapa hueca ni añade componentes internos no documentados.","La pertenencia al conjunto no demuestra apoyo o anclaje directo a la cimentación."] | Geometría de coordinación. Los volúmenes de referencia y subcomponentes no son cantidades de material ni componentes de fabricación certificados. | Sin especificación de material en la documentación revisada | {"documentId":"EQ-IMPLANTACION-20260430","title":"Plano del fabricante: implantación de equipos","sheet":"LHD2609-GD01000 · espacio modelo","date":"2026-04-30","componentSourceHandles":["71428","71618","7189D","7189E","718A2","718A4","718A7","71930","71931","7193B","7193D","72411","7241B","7241C","7241D","72420","72422","72423","72424","72513","729B9","729BB","729BC","72F28","72F2F","72F39","72F3E","72F40","72F54","72F5B","72F5F","72F60","72F63","72F69","72F70","72F73","72F75","72F78","72F79","72F7A","72F7D","72F80","72F84","72F86","72F88","72F89","72F8A","72F8B","72F8C","72F8D","72F8E","72F8F","72F90","72F92","72F9B","72F9D","72F9E","72FB1","72FB2","72FB6","72FB8","72FC0","72FC2","72FCB","72FCD","72FD6","72FD7","72FD8","72FD9","72FDA","72FDB","72FDC","72FDE","72FEC","72FED","72FEE","72FEF","72FF0","72FF1","72FF2","72FF3","72FF4","72FF5","72FF6","72FF7","72FFA","72FFB","72FFC","72FFE","72FFF","73000","73001","73004","73005","73008","73009","7300A","7300B","7300E","7300F","73010","73012","73013","73014","73015","73018","73019","7301C","7301D","7301E","7301F","73022","73023","73024","7302A","7302B","7302C","7302D","73030","73035","73036","7303A","7303C","7303D","7303E","7303F","73040","73041","73042","73047","73048","73049","7304B","7304C","73058","7305C","7305D","7305E","73062","73066","73067","73068","73069","7306A","7306C","7306D","7306F","73070","73071","73072","73073","73074","730A9","730AB","730AC","730AD","730AE","730AF","730B0","730B1","730B2","730B3","730B4","730B5","730B8","730BC","730BD","730BE","730BF","730C0","730C1","730C2","730C3","730C4","730C5","730C7","730C9","730CB","730CC","730CD","730CF","730D2","730D5","730D8","730D9","730DA","730DC","730DF","730E2","730E8","730EB","730EF","730F0","730F1","730F4","730F6","730F7","730F8","730FA","7310B","732E7"]} | yes | equipment_light_gray | [0.88,0.89,0.88] | 0.45 | 0.28 | Referencia visual de fotografías públicas de Jinhong Gas / fabricante. Apariencia provisional para coordinación; fotografías oficiales pueden orientar el color, pero no acreditan el material, el acabado ni el equipo concreto. | La apariencia no certifica el material físico ni el acabado de fabricación. | BIM · Equipos | AC1001C | Compresor de aire AC1001C | IfcCompressor | {"documented":[{"label":"Dimensión X local del bastidor de referencia CAD","value":2.35,"unit":"m","source":"EQ-CARGAS-20260825 · contorno CAD · handles 3F0","status":"derivado"},{"label":"Dimensión Y local del bastidor de referencia CAD","value":5.22,"unit":"m","source":"EQ-CARGAS-20260825 · contorno CAD · handles 3F0","status":"derivado"},{"label":"Altura acotada","value":3.38,"unit":"m","source":"EQ-CARGAS-20260825 · handle 25AF","status":"documentado"},{"label":"Cota relativa de la superficie de apoyo","value":0.4,"unit":"m","source":"LHD2609-JG00100-20260904 · sección 1 / 1-1 · 28C35, 28C38, 28C3B, 28C89","status":"documentado"}],"geometry":[{"label":"Extensión de la malla en X","value":3.177584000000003,"unit":"m","source":"Geometría releída del IFC; datum absoluto de proceso provisional","status":"derivado"},{"label":"Extensión de la malla en Y","value":6.404527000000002,"unit":"m","source":"Geometría releída del IFC; datum absoluto de proceso provisional","status":"derivado"},{"label":"Extensión de la malla en Z","value":3.3800000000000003,"unit":"m","source":"Geometría releída del IFC; datum absoluto de proceso provisional","status":"derivado"},{"label":"Cota inferior de visualización","value":286.5,"unit":"m","source":"Geometría releída del IFC; datum absoluto de proceso provisional","status":"derivado"},{"label":"Cota superior de visualización","value":289.88,"unit":"m","source":"Geometría releída del IFC; datum absoluto de proceso provisional","status":"derivado"}],"notes":["Las extensiones de la malla se miden en los ejes del proyecto tras el giro de implantación; no sustituyen las dimensiones locales del fabricante.","La envolvente, su volumen y los espesores de visualización no son volúmenes de material ni cantidades de compra, construcción o fabricación.","Las dimensiones documentadas distinguen cotas explícitas y medidas extraídas de contornos CAD; las dimensiones geométricas describen únicamente la malla publicada.","Las extensiones de la malla refinada y las dimensiones documentadas del contorno o bastidor tienen distinto alcance; las cotas parciales del detalle son provisionales."]} | {"Estado de la planta":"Derivado del CAD y del giro de implantación","Nivel relativo del apoyo (m)":0.4,"Estado del nivel relativo":"Documentado en el plano de cimentaciones","Cero absoluto de visualización (m)":286.1,"Estado del cero absoluto":"Provisional","Cota del apoyo de visualización (m)":286.5,"Desplazamiento aplicado a la malla (m)":0.40000000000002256,"Criterio":"Nivel de apoyo relativo documentado. Se adopta el cero de proceso a 286,10 m solo para visualización; la equivalencia absoluta no está confirmada. No se añade un espesor de montaje sin cota del fabricante."} | ["La máquina está contenida en la envolvente de la cabina acústica; su superposición no acredita una interferencia física.","El bastidor CAD coincide con la referencia de 2,35 × 5,22 m del plano de cargas, pero cuerpos y auxiliares del detalle de abril sobresalen de esa referencia, hasta aproximadamente 1,048 m por el extremo sur y 0,246 m por el lado oeste. Extensión geométrica resultante: 2,595899 × 6,268101 × 3,38 m, derivada y pendiente de coordinación entre revisiones. Permanecen dentro de la cabina acústica. Compatibilidad de revisión pendiente de fabricante.","Todas las alturas parciales son hipótesis de visualización; solo la altura total de 3,38 m está acotada.","Las regiones del dibujo se usan como envolventes de cuerpos; la identificación funcional y la cota Z de cada pieza requieren verificación.","Pequeños taladros, tornillería y detalles interiores de las regiones no se extruyen como vacíos de fabricación.","El bastidor documentado mide 2,35 × 5,22 m. Los accesorios del detalle de abril sobresalen; el conjunto refinado ocupa aproximadamente 2,596 × 6,268 m en ejes del fabricante, pendiente de coordinación entre revisiones.","El acabado de grout HA-35 de 50 mm termina en +0,400; el hormigón termina en +0,350. La losa MAC contigua termina en +0,200.","El cero absoluto de la revisión no está definido; 286,10 m sigue siendo una hipótesis de coordinación.","Se alinea el punto inferior del conjunto del equipo, incluidos los pies ya representados, con la superficie de apoyo terminada; no se añade un espesor de calzos, placa o grout del fabricante no documentado."] | {"revision":"Detalle en planta de 2026-04-30 coordinado de forma preliminar con envolventes y alturas de 2026-08-25","status":"provisional","verticalRule":"Altura total documentada: 3,38 m. Plataforma gráfica de 0,15 m; los cuerpos extraídos de la planta reciben alturas provisionales entre 1,00 y 3,38 m, detalladas por subvolumen. No se dispone de alzado acotado de cada componente.","partCount":26,"source":{"documentId":"EQ-IMPLANTACION-20260430","title":"Plano del fabricante: implantación de equipos","sheet":"LHD2609-GD01000 · espacio modelo","date":"2026-04-30"},"heightSource":{"documentId":"EQ-CARGAS-20260825","title":"Plano del fabricante: cargas de equipos","sheet":"Espacio modelo","date":"2026-08-25"},"unconfirmedDimensions":["Todas las alturas parciales son hipótesis de visualización; solo la altura total de 3,38 m está acotada.","Las regiones del dibujo se usan como envolventes de cuerpos; la identificación funcional y la cota Z de cada pieza requieren verificación.","Pequeños taladros, tornillería y detalles interiores de las regiones no se extruyen como vacíos de fabricación."],"quantityUse":"Magnitudes de la geometría representada; no son cantidades de material, obra, compra, capacidad útil ni fabricación. En geometrías compuestas se suman superficies y volúmenes de partes y pueden existir solapes no depurados.","partsAreBOM":false} | equipment_component | {"min":[60.820401,68.378413,1.5],"max":[63.997985,74.78294,4.88]} | {"boundingBoxM":{"min":[60.820401,68.378413,1.5],"max":[63.997985,74.78294,4.88]},"extentsM":[3.177584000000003,6.404527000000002,3.38],"meshSurfaceM2":165.19823143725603,"meshVolumeM3":20.170106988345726,"closedSolid":true,"windingConsistent":true,"basis":"Submalla exacta de los triángulos del modelo IFC coordinado; separación de componentes sin transformación ni retesselación."} | ["Todas las alturas parciales son hipótesis de visualización; solo la altura total de 3,38 m está acotada.","Las regiones del dibujo se usan como envolventes de cuerpos; la identificación funcional y la cota Z de cada pieza requieren verificación.","Pequeños taladros, tornillería y detalles interiores de las regiones no se extruyen como vacíos de fabricación.","La separación gráfica no aporta cotas de fabricación ni identifica piezas internas no documentadas.","Los materiales y acabados permanecen provisionales; las fotografías públicas solo orientan la apariencia."] | {"id":"AC1001C--cad-region-014","sourcePartId":"AC1001C--cad-region-014","name":"Cuerpo de equipo · región CAD 14","role":"equipment_component","classificationStatus":"provisional","classificationBasis":"Rol del subvolumen gráfico según el activo de detalle; identidad de fabricación no confirmada.","parentEquipmentId":"AC1001C","parentEquipmentGuid":"2IJ0PLLizIvfouRXAkczXf","isAssemblyIdentityCarrier":false,"sourceFaceRange":[640,1192],"sourceCurrentFaceIndices":[640,641,642,643,644,645,646,647,648,649,650,651,652,653,654,655,656,657,658,659,660,661,662,663,664,665,666,667,668,669,670,671,672,673,674,675,676,677,678,679,680,681,682,683,684,685,686,687,688,689,690,691,692,693,694,695,696,697,698,699,700,701,702,703,704,705,706,707,708,709,710,711,712,713,714,715,716,717,718,719,720,721,722,723,724,725,726,727,728,729,730,731,732,733,734,735,736,737,738,739,740,741,742,743,744,745,746,747,748,749,750,751,752,753,754,755,756,757,758,759,760,761,762,763,764,765,766,767,768,769,770,771,772,773,774,775,776,777,778,779,780,781,782,783,784,785,786,787,788,789,790,791,792,793,794,795,796,797,798,799,800,801,802,803,804,805,806,807,808,809,810,811,812,813,814,815,816,817,818,819,820,821,822,823,824,825,826,827,828,829,830,831,832,833,834,835,836,837,838,839,840,841,842,843,844,845,846,847,848,849,850,851,852,853,854,855,856,857,858,859,860,861,862,863,864,865,866,867,868,869,870,871,872,873,874,875,876,877,878,879,880,881,882,883,884,885,886,887,888,889,890,891,892,893,894,895,896,897,898,899,900,901,902,903,904,905,906,907,908,909,910,911,912,913,914,915,916,917,918,919,920,921,922,923,924,925,926,927,928,929,930,931,932,933,934,935,936,937,938,939,940,941,942,943,944,945,946,947,948,949,950,951,952,953,954,955,956,957,958,959,960,961,962,963,964,965,966,967,968,969,970,971,972,973,974,975,976,977,978,979,980,981,982,983,984,985,986,987,988,989,990,991,992,993,994,995,996,997,998,999,1000,1001,1002,1003,1004,1005,1006,1007,1008,1009,1010,1011,1012,1013,1014,1015,1016,1017,1018,1019,1020,1021,1022,1023,1024,1025,1026,1027,1028,1029,1030,1031,1032,1033,1034,1035,1036,1037,1038,1039,1040,1041,1042,1043,1044,1045,1046,1047,1048,1049,1050,1051,1052,1053,1054,1055,1056,1057,1058,1059,1060,1061,1062,1063,1064,1065,1066,1067,1068,1069,1070,1071,1072,1073,1074,1075,1076,1077,1078,1079,1080,1081,1082,1083,1084,1085,1086,1087,1088,1089,1090,1091,1092,1093,1094,1095,1096,1097,1098,1099,1100,1101,1102,1103,1104,1105,1106,1107,1108,1109,1110,1111,1112,1113,1114,1115,1116,1117,1118,1119,1120,1121,1122,1123,1124,1125,1126,1127,1128,1129,1130,1131,1132,1133,1134,1135,1136,1137,1138,1139,1140,1141,1142,1143,1144,1145,1146,1147,1148,1149,1150,1151,1152,1153,1154,1155,1156,1157,1158,1159,1160,1161,1162,1163,1164,1165,1166,1167,1168,1169,1170,1171,1172,1173,1174,1175,1176,1177,1178,1179,1180,1181,1182,1183,1184,1185,1186,1187,1188,1189,1190,1191],"sourceMeshSha256":"7b60c904c9d84d22fded9be34af09a09a9c198ec8e75e61902634d5e4064c761","sourceVertexIndices":[346,347,348,349,350,351,352,353,354,355,356,357,358,359,360,361,362,363,364,365,366,367,368,369,370,371,372,373,374,375,376,377,378,379,380,381,382,383,384,385,386,387,388,389,390,391,392,393,394,395,396,397,398,399,400,401,402,403,404,405,406,407,408,409,410,411,412,413,414,415,416,417,418,419,420,421,422,423,424,425,426,427,428,429,430,431,432,433,434,435,436,437,438,439,440,441,442,443,444,445,446,447,448,449,450,451,452,453,454,455,456,457,458,459,460,461,462,463,464,465,466,467,468,469,470,471,472,473,474,475,476,477,478,479,480,481,482,483,484,485,486,487,488,489,490,491,492,493,494,495,496,497,498,499,500,501,502,503,504,505,506,507,508,509,510,511,512,513,514,515,516,517,518,519,520,521,522,523,524,525,526,527,528,529,530,531,532,533,534,535,536,537,538,539,540,541,542,543,544,545,546,547,548,549,550,551,552,553,554,555,556,557,558,559,560,561,562,563,564,565,566,567,568,569,570,571,572,573,574,575,576,577,578,579,580,581,582,583,584,585,586,587,588,589,590,591,592,593,594,595,596,597,598,599,600,601,602,603,604,605,606,607,608,609,610,611,612,613,614,615,616,617,618,619,620,621,622,623],"separationMethod":"Partición exacta de triángulos existentes; coordenadas y orientación de caras conservadas.","quantityUse":"Magnitudes geométricas del subvolumen; no son cantidades netas de material, fabricación, suministro o capacidad."} | {"id":"AC1001C","name":"Compresor de aire AC1001C","relationship":"decomposed_component","parentShapeMeaning":"La forma del objeto que conserva el ID del equipo es únicamente su componente principal; el conjunto completo requiere sus hijos."} | {"kind":"through_parent","parentEquipmentId":"AC1001C","directAnchorageVerified":false,"note":"La relación del conjunto con cimentaciones se conserva en el objeto que mantiene el ID del equipo; no se atribuye fijación directa a cada subcomponente."} | Documento de implantación y apoyo del conjunto padre; no acredita fijación individual de este componente. | AC1001C--cad-region-014 | Cuerpo de equipo · región CAD 14 | Equipos | unknown | equipment_light_gray | {"documentId":"EQ-IMPLANTACION-20260430","title":"Plano del fabricante: implantación de equipos","sheet":"LHD2609-GD01000 · espacio modelo","date":"2026-04-30","componentSourceHandles":["71428","71618","7189D","7189E","718A2","718A4","718A7","71930","71931","7193B","7193D","72411","7241B","7241C","7241D","72420","72422","72423","72424","72513","729B9","729BB","729BC","72F28","72F2F","72F39","72F3E","72F40","72F54","72F5B","72F5F","72F60","72F63","72F69","72F70","72F73","72F75","72F78","72F79","72F7A","72F7D","72F80","72F84","72F86","72F88","72F89","72F8A","72F8B","72F8C","72F8D","72F8E","72F8F","72F90","72F92","72F9B","72F9D","72F9E","72FB1","72FB2","72FB6","72FB8","72FC0","72FC2","72FCB","72FCD","72FD6","72FD7","72FD8","72FD9","72FDA","72FDB","72FDC","72FDE","72FEC","72FED","72FEE","72FEF","72FF0","72FF1","72FF2","72FF3","72FF4","72FF5","72FF6","72FF7","72FFA","72FFB","72FFC","72FFE","72FFF","73000","73001","73004","73005","73008","73009","7300A","7300B","7300E","7300F","73010","73012","73013","73014","73015","73018","73019","7301C","7301D","7301E","7301F","73022","73023","73024","7302A","7302B","7302C","7302D","73030","73035","73036","7303A","7303C","7303D","7303E","7303F","73040","73041","73042","73047","73048","73049","7304B","7304C","73058","7305C","7305D","7305E","73062","73066","73067","73068","73069","7306A","7306C","7306D","7306F","73070","73071","73072","73073","73074","730A9","730AB","730AC","730AD","730AE","730AF","730B0","730B1","730B2","730B3","730B4","730B5","730B8","730BC","730BD","730BE","730BF","730C0","730C1","730C2","730C3","730C4","730C5","730C7","730C9","730CB","730CC","730CD","730CF","730D2","730D5","730D8","730D9","730DA","730DC","730DF","730E2","730E8","730EB","730EF","730F0","730F1","730F4","730F6","730F7","730F8","730FA","7310B","732E7"]} | Submalla de triángulos existentes; no hay nueva posición ni nuevas caras. | Cotas globales del conjunto conservadas aparte; las dimensiones de esta ficha son de la submalla. | Coordinación del conjunto padre; anclaje directo individual no acreditado. | Superficie y volumen geométricos brutos; no constituyen cantidades netas de obra, material o fabricación. | Plano general y dimensiones globales de AC1001C; no se asignan esas dimensiones globales a este componente. | ["71428","71618","7189D","7189E","718A2","718A4","718A7","71930","71931","7193B","7193D","72411","7241B","7241C","7241D","72420","72422","72423","72424","72513","729B9","729BB","729BC","72F28","72F2F","72F39","72F3E","72F40","72F54","72F5B","72F5F","72F60","72F63","72F69","72F70","72F73","72F75","72F78","72F79","72F7A","72F7D","72F80","72F84","72F86","72F88","72F89","72F8A","72F8B","72F8C","72F8D","72F8E","72F8F","72F90","72F92","72F9B","72F9D","72F9E","72FB1","72FB2","72FB6","72FB8","72FC0","72FC2","72FCB","72FCD","72FD6","72FD7","72FD8","72FD9","72FDA","72FDB","72FDC","72FDE","72FEC","72FED","72FEE","72FEF","72FF0","72FF1","72FF2","72FF3","72FF4","72FF5","72FF6","72FF7","72FFA","72FFB","72FFC","72FFE","72FFF","73000","73001","73004","73005","73008","73009","7300A","7300B","7300E","7300F","73010","73012","73013","73014","73015","73018","73019","7301C","7301D","7301E","7301F","73022","73023","73024","7302A","7302B","7302C","7302D","73030","73035","73036","7303A","7303C","7303D","7303E","7303F","73040","73041","73042","73047","73048","73049","7304B","7304C","73058","7305C","7305D","7305E","73062","73066","73067","73068","73069","7306A","7306C","7306D","7306F","73070","73071","73072","73073","73074","730A9","730AB","730AC","730AD","730AE","730AF","730B0","730B1","730B2","730B3","730B4","730B5","730B8","730BC","730BD","730BE","730BF","730C0","730C1","730C2","730C3","730C4","730C5","730C7","730C9","730CB","730CC","730CD","730CF","730D2","730D5","730D8","730D9","730DA","730DC","730DF","730E2","730E8","730EB","730EF","730F0","730F1","730F4","730F6","730F7","730F8","730FA","7310B","732E7"] | 1 | no | Submalla exacta; interpretación funcional y cotas parciales provisionales.
Compresor de aire AC1001C · Cuerpo de equipo · región CAD 15 | Componente de equipo · cuerpo o accesorio | Plano del fabricante: implantación de equipos · referencia E7 | 0.194593 | 0.520447 | 1.9 | 286.65 | 288.55 | 2.63388 | 0.12442 | Apoyo relativo +0.400 m; cero absoluto provisional | Componente de equipo · cuerpo o accesorio | equipmentComponent | {"name":"No especificado","source":"Sin especificación de material en la documentación revisada","status":"unknown"} | {"documented":[{"label":"Referencia dimensional del conjunto","value":"Plano general y dimensiones globales de AC1001C; no se asignan esas dimensiones globales a este componente.","unit":"","source":"EQ-IMPLANTACION-20260430 · LHD2609-GD01000 · espacio modelo","status":"referencia_del_conjunto"}],"geometry":[{"label":"Extensión de la malla en X","value":0.19459299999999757,"unit":"m","source":"Geometría releída del IFC; datum absoluto de proceso provisional","status":"derivado"},{"label":"Extensión de la malla en Y","value":0.5204470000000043,"unit":"m","source":"Geometría releída del IFC; datum absoluto de proceso provisional","status":"derivado"},{"label":"Extensión de la malla en Z","value":1.9,"unit":"m","source":"Geometría releída del IFC; datum absoluto de proceso provisional","status":"derivado"},{"label":"Cota inferior de visualización","value":286.65,"unit":"m","source":"Geometría releída del IFC; datum absoluto de proceso provisional","status":"derivado"},{"label":"Cota superior de visualización","value":288.55,"unit":"m","source":"Geometría releída del IFC; datum absoluto de proceso provisional","status":"derivado"}],"notes":["Las dimensiones del equipo completo se conservan en parentEquipmentDimensions.","Las extensiones en X/Y son de los ejes del modelo y no sustituyen cotas locales de fabricación.","No se infieren espesores de chapa, tolerancias ni dimensiones de piezas a partir de la partición."]} | {"documentId":"EQ-IMPLANTACION-20260430","title":"Plano del fabricante: implantación de equipos","sheet":"LHD2609-GD01000 · espacio modelo","date":"2026-04-30","componentSourceHandles":["71619","71674","71675","71679","7167A","71780","71781","718A0","718A5","718A9","718AC","7251F","72523","72524","72F34","72F36","72F37","72F38","72F3C","72F41","72F51","72F55","72F5C","72F61","72F65","72F68","72F6A","72F6F","72F72","72F74","72F7B","72F7C","72F7E","72F83","72F85","72F87","72F8B","72F98","72F99","72F9A","72FD3","72FD4","73027","73028","73029","7302A","7302E","7302F","73031","73037","7303C","7303D","7303F","73076","73077","73078","73079","7307A","7307B","7307C","7307D","7307E","73085","73086","73089","7308A","73091","73092","73094","73095","73096","7309A","7309B","7309C","7309E","7309F","730A0","730A2","730A5","730A6","730A7","730A8","730AA","730E6","730E7","730EC","730ED","730EE","730F2","730FC","732E7","73468","734A1"]} | {"horizontalStatus":"derivado_del_conjunto","verticalStatus":"derivado_del_conjunto","coordinateSystem":"model_local_m","parentEquipmentId":"AC1001C","transformApplied":false,"note":"Coordenadas copiadas exactamente del equipo coordinado; no se ha movido, girado, elevado ni reescalado este componente.","foundationRelationship":"El apoyo y las cotas de instalación se documentan para el conjunto padre. Esta submalla no acredita un anclaje directo.","meshMinimumAbsoluteElevationM":286.65,"assemblyPlacementField":"parentEquipmentPositioning"} | ["Componente separado de una reconstrucción documental del conjunto. Las alturas y detalles parciales conservan las limitaciones del fabricante registradas en parentEquipmentIssues.","Esta representación exterior no crea una chapa hueca ni añade componentes internos no documentados.","La pertenencia al conjunto no demuestra apoyo o anclaje directo a la cimentación."] | {"source":{"documentId":"EQ-IMPLANTACION-20260430","title":"Plano del fabricante: implantación de equipos","sheet":"LHD2609-GD01000 · espacio modelo","date":"2026-04-30","componentSourceHandles":["71619","71674","71675","71679","7167A","71780","71781","718A0","718A5","718A9","718AC","7251F","72523","72524","72F34","72F36","72F37","72F38","72F3C","72F41","72F51","72F55","72F5C","72F61","72F65","72F68","72F6A","72F6F","72F72","72F74","72F7B","72F7C","72F7E","72F83","72F85","72F87","72F8B","72F98","72F99","72F9A","72FD3","72FD4","73027","73028","73029","7302A","7302E","7302F","73031","73037","7303C","7303D","7303F","73076","73077","73078","73079","7307A","7307B","7307C","7307D","7307E","73085","73086","73089","7308A","73091","73092","73094","73095","73096","7309A","7309B","7309C","7309E","7309F","730A0","730A2","730A5","730A6","730A7","730A8","730AA","730E6","730E7","730EC","730ED","730EE","730F2","730FC","732E7","73468","734A1"]},"sourcePartId":"AC1001C--cad-region-015","sourceHandles":["71619","71674","71675","71679","7167A","71780","71781","718A0","718A5","718A9","718AC","7251F","72523","72524","72F34","72F36","72F37","72F38","72F3C","72F41","72F51","72F55","72F5C","72F61","72F65","72F68","72F6A","72F6F","72F72","72F74","72F7B","72F7C","72F7E","72F83","72F85","72F87","72F8B","72F98","72F99","72F9A","72FD3","72FD4","73027","73028","73029","7302A","7302E","7302F","73031","73037","7303C","7303D","7303F","73076","73077","73078","73079","7307A","7307B","7307C","7307D","7307E","73085","73086","73089","7308A","73091","73092","73094","73095","73096","7309A","7309B","7309C","7309E","7309F","730A0","730A2","730A5","730A6","730A7","730A8","730AA","730E6","730E7","730EC","730ED","730EE","730F2","730FC","732E7","73468","734A1"],"partCount":1,"partsAreBOM":false,"status":"Submalla exacta; interpretación funcional y cotas parciales provisionales."} | {"boundingBoxM":{"min":[62.256655,71.83505,1.65],"max":[62.451248,72.355497,3.55]},"extentsM":[0.194593,0.520447,1.9],"meshSurfaceM2":2.633876,"meshVolumeM3":0.12442,"closedSolid":true,"basis":"Geometría de coordinación. Los volúmenes de referencia y subcomponentes no son cantidades de material ni componentes de fabricación certificados."} | {"documentId":"LHD2609-JG00100-20260904","title":"Cimentaciones y pedestales de equipos · revisión recibida 04/09/2026","date":"2026-09-04","sheet":"1 / 1-1","sourceHandles":["28C35","28C38","28C3B","28C89"]} | equipment | {"id":"equipment","name":"Equipos"} | {"profileId":"equipment_light_gray","name":"Equipo · gris claro provisional","materialName":"No especificado","physicalMaterialStatus":"unknown","physicalMaterialSource":"Sin especificación de material en la documentación revisada","appearanceStatus":"provisional","appearanceBasis":"Referencia visual de fotografías públicas de Jinhong Gas / fabricante. Apariencia provisional para coordinación; fotografías oficiales pueden orientar el color, pero no acreditan el material, el acabado ni el equipo concreto.","appearanceReferences":["jinhong-official-asu"],"note":"El perfil visual no confirma material, grado ni acabado del componente."} | {"status":"componente_independiente","note":"Objeto independiente seleccionable. Las caras se asignan una sola vez entre todos los componentes del conjunto.","parentEquipmentId":"AC1001C","isAssemblyIdentityCarrier":false} | {"elementId":"AC1001C--cad-region-015","ifcGuid":"2xXyNKyrbSTwqWOvoxaByT","ifcClass":"IfcBuildingElementProxy","buildingId":"process_plant","buildingName":"Planta de proceso","sourceDocumentId":"EQ-IMPLANTACION-20260430","sourceRepresentationKind":"equipmentComponent"} | {"layerId":"equipment","layerName":"Equipos","role":"Componente de equipo · cuerpo o accesorio","basis":"Clasificación por función del elemento; no modifica las especificaciones documentales."} | {"profileId":"equipment_light_gray","name":"Equipo · gris claro provisional","status":"provisional","basis":"Referencia visual de fotografías públicas de Jinhong Gas / fabricante. Apariencia provisional para coordinación; fotografías oficiales pueden orientar el color, pero no acreditan el material, el acabado ni el equipo concreto.","physicalMaterialUnchanged":true} | Equipos | No especificado | Equipos | Equipo · gris claro provisional | provisional | AC1001C--cad-region-015 | ["Componente separado de una reconstrucción documental del conjunto. Las alturas y detalles parciales conservan las limitaciones del fabricante registradas en parentEquipmentIssues.","Esta representación exterior no crea una chapa hueca ni añade componentes internos no documentados.","La pertenencia al conjunto no demuestra apoyo o anclaje directo a la cimentación."] | Geometría de coordinación. Los volúmenes de referencia y subcomponentes no son cantidades de material ni componentes de fabricación certificados. | Sin especificación de material en la documentación revisada | {"documentId":"EQ-IMPLANTACION-20260430","title":"Plano del fabricante: implantación de equipos","sheet":"LHD2609-GD01000 · espacio modelo","date":"2026-04-30","componentSourceHandles":["71619","71674","71675","71679","7167A","71780","71781","718A0","718A5","718A9","718AC","7251F","72523","72524","72F34","72F36","72F37","72F38","72F3C","72F41","72F51","72F55","72F5C","72F61","72F65","72F68","72F6A","72F6F","72F72","72F74","72F7B","72F7C","72F7E","72F83","72F85","72F87","72F8B","72F98","72F99","72F9A","72FD3","72FD4","73027","73028","73029","7302A","7302E","7302F","73031","73037","7303C","7303D","7303F","73076","73077","73078","73079","7307A","7307B","7307C","7307D","7307E","73085","73086","73089","7308A","73091","73092","73094","73095","73096","7309A","7309B","7309C","7309E","7309F","730A0","730A2","730A5","730A6","730A7","730A8","730AA","730E6","730E7","730EC","730ED","730EE","730F2","730FC","732E7","73468","734A1"]} | yes | equipment_light_gray | [0.88,0.89,0.88] | 0.45 | 0.28 | Referencia visual de fotografías públicas de Jinhong Gas / fabricante. Apariencia provisional para coordinación; fotografías oficiales pueden orientar el color, pero no acreditan el material, el acabado ni el equipo concreto. | La apariencia no certifica el material físico ni el acabado de fabricación. | BIM · Equipos | AC1001C | Compresor de aire AC1001C | IfcCompressor | {"documented":[{"label":"Dimensión X local del bastidor de referencia CAD","value":2.35,"unit":"m","source":"EQ-CARGAS-20260825 · contorno CAD · handles 3F0","status":"derivado"},{"label":"Dimensión Y local del bastidor de referencia CAD","value":5.22,"unit":"m","source":"EQ-CARGAS-20260825 · contorno CAD · handles 3F0","status":"derivado"},{"label":"Altura acotada","value":3.38,"unit":"m","source":"EQ-CARGAS-20260825 · handle 25AF","status":"documentado"},{"label":"Cota relativa de la superficie de apoyo","value":0.4,"unit":"m","source":"LHD2609-JG00100-20260904 · sección 1 / 1-1 · 28C35, 28C38, 28C3B, 28C89","status":"documentado"}],"geometry":[{"label":"Extensión de la malla en X","value":3.177584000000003,"unit":"m","source":"Geometría releída del IFC; datum absoluto de proceso provisional","status":"derivado"},{"label":"Extensión de la malla en Y","value":6.404527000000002,"unit":"m","source":"Geometría releída del IFC; datum absoluto de proceso provisional","status":"derivado"},{"label":"Extensión de la malla en Z","value":3.3800000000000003,"unit":"m","source":"Geometría releída del IFC; datum absoluto de proceso provisional","status":"derivado"},{"label":"Cota inferior de visualización","value":286.5,"unit":"m","source":"Geometría releída del IFC; datum absoluto de proceso provisional","status":"derivado"},{"label":"Cota superior de visualización","value":289.88,"unit":"m","source":"Geometría releída del IFC; datum absoluto de proceso provisional","status":"derivado"}],"notes":["Las extensiones de la malla se miden en los ejes del proyecto tras el giro de implantación; no sustituyen las dimensiones locales del fabricante.","La envolvente, su volumen y los espesores de visualización no son volúmenes de material ni cantidades de compra, construcción o fabricación.","Las dimensiones documentadas distinguen cotas explícitas y medidas extraídas de contornos CAD; las dimensiones geométricas describen únicamente la malla publicada.","Las extensiones de la malla refinada y las dimensiones documentadas del contorno o bastidor tienen distinto alcance; las cotas parciales del detalle son provisionales."]} | {"Estado de la planta":"Derivado del CAD y del giro de implantación","Nivel relativo del apoyo (m)":0.4,"Estado del nivel relativo":"Documentado en el plano de cimentaciones","Cero absoluto de visualización (m)":286.1,"Estado del cero absoluto":"Provisional","Cota del apoyo de visualización (m)":286.5,"Desplazamiento aplicado a la malla (m)":0.40000000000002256,"Criterio":"Nivel de apoyo relativo documentado. Se adopta el cero de proceso a 286,10 m solo para visualización; la equivalencia absoluta no está confirmada. No se añade un espesor de montaje sin cota del fabricante."} | ["La máquina está contenida en la envolvente de la cabina acústica; su superposición no acredita una interferencia física.","El bastidor CAD coincide con la referencia de 2,35 × 5,22 m del plano de cargas, pero cuerpos y auxiliares del detalle de abril sobresalen de esa referencia, hasta aproximadamente 1,048 m por el extremo sur y 0,246 m por el lado oeste. Extensión geométrica resultante: 2,595899 × 6,268101 × 3,38 m, derivada y pendiente de coordinación entre revisiones. Permanecen dentro de la cabina acústica. Compatibilidad de revisión pendiente de fabricante.","Todas las alturas parciales son hipótesis de visualización; solo la altura total de 3,38 m está acotada.","Las regiones del dibujo se usan como envolventes de cuerpos; la identificación funcional y la cota Z de cada pieza requieren verificación.","Pequeños taladros, tornillería y detalles interiores de las regiones no se extruyen como vacíos de fabricación.","El bastidor documentado mide 2,35 × 5,22 m. Los accesorios del detalle de abril sobresalen; el conjunto refinado ocupa aproximadamente 2,596 × 6,268 m en ejes del fabricante, pendiente de coordinación entre revisiones.","El acabado de grout HA-35 de 50 mm termina en +0,400; el hormigón termina en +0,350. La losa MAC contigua termina en +0,200.","El cero absoluto de la revisión no está definido; 286,10 m sigue siendo una hipótesis de coordinación.","Se alinea el punto inferior del conjunto del equipo, incluidos los pies ya representados, con la superficie de apoyo terminada; no se añade un espesor de calzos, placa o grout del fabricante no documentado."] | {"revision":"Detalle en planta de 2026-04-30 coordinado de forma preliminar con envolventes y alturas de 2026-08-25","status":"provisional","verticalRule":"Altura total documentada: 3,38 m. Plataforma gráfica de 0,15 m; los cuerpos extraídos de la planta reciben alturas provisionales entre 1,00 y 3,38 m, detalladas por subvolumen. No se dispone de alzado acotado de cada componente.","partCount":26,"source":{"documentId":"EQ-IMPLANTACION-20260430","title":"Plano del fabricante: implantación de equipos","sheet":"LHD2609-GD01000 · espacio modelo","date":"2026-04-30"},"heightSource":{"documentId":"EQ-CARGAS-20260825","title":"Plano del fabricante: cargas de equipos","sheet":"Espacio modelo","date":"2026-08-25"},"unconfirmedDimensions":["Todas las alturas parciales son hipótesis de visualización; solo la altura total de 3,38 m está acotada.","Las regiones del dibujo se usan como envolventes de cuerpos; la identificación funcional y la cota Z de cada pieza requieren verificación.","Pequeños taladros, tornillería y detalles interiores de las regiones no se extruyen como vacíos de fabricación."],"quantityUse":"Magnitudes de la geometría representada; no son cantidades de material, obra, compra, capacidad útil ni fabricación. En geometrías compuestas se suman superficies y volúmenes de partes y pueden existir solapes no depurados.","partsAreBOM":false} | equipment_component | {"min":[60.820401,68.378413,1.5],"max":[63.997985,74.78294,4.88]} | {"boundingBoxM":{"min":[60.820401,68.378413,1.5],"max":[63.997985,74.78294,4.88]},"extentsM":[3.177584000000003,6.404527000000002,3.38],"meshSurfaceM2":165.19823143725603,"meshVolumeM3":20.170106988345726,"closedSolid":true,"windingConsistent":true,"basis":"Submalla exacta de los triángulos del modelo IFC coordinado; separación de componentes sin transformación ni retesselación."} | ["Todas las alturas parciales son hipótesis de visualización; solo la altura total de 3,38 m está acotada.","Las regiones del dibujo se usan como envolventes de cuerpos; la identificación funcional y la cota Z de cada pieza requieren verificación.","Pequeños taladros, tornillería y detalles interiores de las regiones no se extruyen como vacíos de fabricación.","La separación gráfica no aporta cotas de fabricación ni identifica piezas internas no documentadas.","Los materiales y acabados permanecen provisionales; las fotografías públicas solo orientan la apariencia."] | {"id":"AC1001C--cad-region-015","sourcePartId":"AC1001C--cad-region-015","name":"Cuerpo de equipo · región CAD 15","role":"equipment_component","classificationStatus":"provisional","classificationBasis":"Rol del subvolumen gráfico según el activo de detalle; identidad de fabricación no confirmada.","parentEquipmentId":"AC1001C","parentEquipmentGuid":"2IJ0PLLizIvfouRXAkczXf","isAssemblyIdentityCarrier":false,"sourceFaceRange":[1192,1256],"sourceCurrentFaceIndices":[1192,1193,1194,1195,1196,1197,1198,1199,1200,1201,1202,1203,1204,1205,1206,1207,1208,1209,1210,1211,1212,1213,1214,1215,1216,1217,1218,1219,1220,1221,1222,1223,1224,1225,1226,1227,1228,1229,1230,1231,1232,1233,1234,1235,1236,1237,1238,1239,1240,1241,1242,1243,1244,1245,1246,1247,1248,1249,1250,1251,1252,1253,1254,1255],"sourceMeshSha256":"7b60c904c9d84d22fded9be34af09a09a9c198ec8e75e61902634d5e4064c761","sourceVertexIndices":[624,625,626,627,628,629,630,631,632,633,634,635,636,637,638,639,640,641,642,643,644,645,646,647,648,649,650,651,652,653,654,655,656,657],"separationMethod":"Partición exacta de triángulos existentes; coordenadas y orientación de caras conservadas.","quantityUse":"Magnitudes geométricas del subvolumen; no son cantidades netas de material, fabricación, suministro o capacidad."} | {"id":"AC1001C","name":"Compresor de aire AC1001C","relationship":"decomposed_component","parentShapeMeaning":"La forma del objeto que conserva el ID del equipo es únicamente su componente principal; el conjunto completo requiere sus hijos."} | {"kind":"through_parent","parentEquipmentId":"AC1001C","directAnchorageVerified":false,"note":"La relación del conjunto con cimentaciones se conserva en el objeto que mantiene el ID del equipo; no se atribuye fijación directa a cada subcomponente."} | Documento de implantación y apoyo del conjunto padre; no acredita fijación individual de este componente. | AC1001C--cad-region-015 | Cuerpo de equipo · región CAD 15 | Equipos | unknown | equipment_light_gray | {"documentId":"EQ-IMPLANTACION-20260430","title":"Plano del fabricante: implantación de equipos","sheet":"LHD2609-GD01000 · espacio modelo","date":"2026-04-30","componentSourceHandles":["71619","71674","71675","71679","7167A","71780","71781","718A0","718A5","718A9","718AC","7251F","72523","72524","72F34","72F36","72F37","72F38","72F3C","72F41","72F51","72F55","72F5C","72F61","72F65","72F68","72F6A","72F6F","72F72","72F74","72F7B","72F7C","72F7E","72F83","72F85","72F87","72F8B","72F98","72F99","72F9A","72FD3","72FD4","73027","73028","73029","7302A","7302E","7302F","73031","73037","7303C","7303D","7303F","73076","73077","73078","73079","7307A","7307B","7307C","7307D","7307E","73085","73086","73089","7308A","73091","73092","73094","73095","73096","7309A","7309B","7309C","7309E","7309F","730A0","730A2","730A5","730A6","730A7","730A8","730AA","730E6","730E7","730EC","730ED","730EE","730F2","730FC","732E7","73468","734A1"]} | Submalla de triángulos existentes; no hay nueva posición ni nuevas caras. | Cotas globales del conjunto conservadas aparte; las dimensiones de esta ficha son de la submalla. | Coordinación del conjunto padre; anclaje directo individual no acreditado. | Superficie y volumen geométricos brutos; no constituyen cantidades netas de obra, material o fabricación. | Plano general y dimensiones globales de AC1001C; no se asignan esas dimensiones globales a este componente. | ["71619","71674","71675","71679","7167A","71780","71781","718A0","718A5","718A9","718AC","7251F","72523","72524","72F34","72F36","72F37","72F38","72F3C","72F41","72F51","72F55","72F5C","72F61","72F65","72F68","72F6A","72F6F","72F72","72F74","72F7B","72F7C","72F7E","72F83","72F85","72F87","72F8B","72F98","72F99","72F9A","72FD3","72FD4","73027","73028","73029","7302A","7302E","7302F","73031","73037","7303C","7303D","7303F","73076","73077","73078","73079","7307A","7307B","7307C","7307D","7307E","73085","73086","73089","7308A","73091","73092","73094","73095","73096","7309A","7309B","7309C","7309E","7309F","730A0","730A2","730A5","730A6","730A7","730A8","730AA","730E6","730E7","730EC","730ED","730EE","730F2","730FC","732E7","73468","734A1"] | 1 | no | Submalla exacta; interpretación funcional y cotas parciales provisionales.
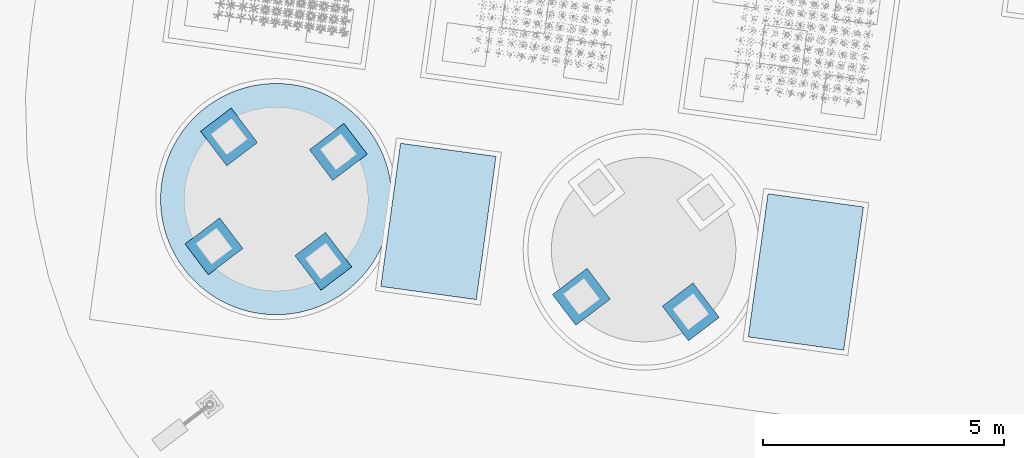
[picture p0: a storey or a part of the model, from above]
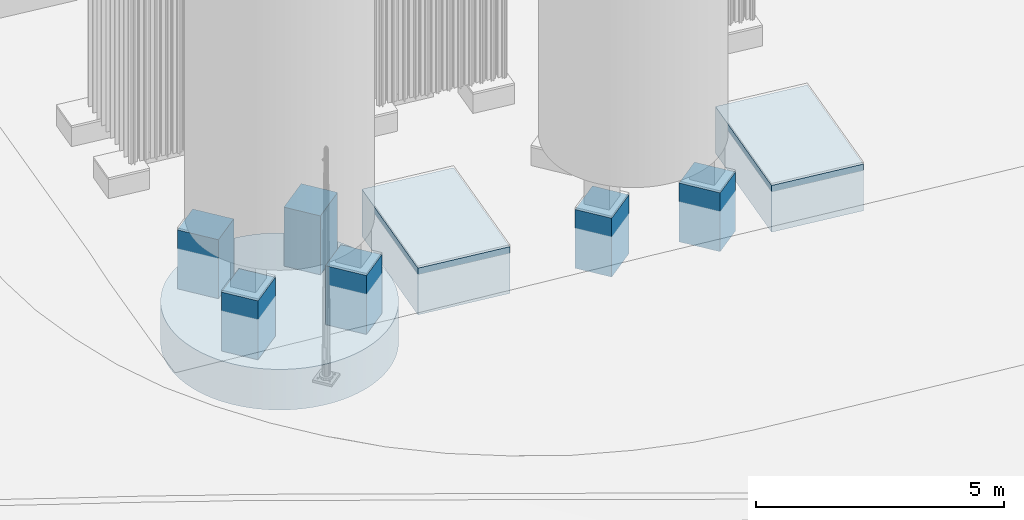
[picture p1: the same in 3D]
Properties of the parts of a building model (IFC4), part 49 of 134

# IfcBuildingElementProxy (140)
Name | Description | Document | Extensión de la malla en X (m) = ExtensionX (m) | Extensión de la malla en Y (m) = ExtensionY (m) | Extensión de la malla en Z (m) = ExtensionZ (m) | Cota inferior de visualización (m) | Cota superior de visualización (m) | SuperficieDeLaMalla (m2) | VolumenGeometrico (m3) | level | category = Categoria = Funcion | representationKind | material | dimensions | JH_InformacionBIM, source = DocumentoFuente | positioning = PosicionYEstado | issues | detailGeometry | geometryMetrics | installationSource | layerId = IdentificadorCapa | visualLayer | materialAppearance | componentSeparation | visualizationIdentity | classification | appearance | Disciplina | Material | Capa BIM = NombreCapa | Acabado de visualización = Acabado | Estado del acabado = Estado | Identificador | JH_Trazabilidad, IncidenciasPendientes | UsoDeLasMagnitudes | JH_EvidenciaDeMaterial, source | JH_DetalleGeometrico, source | VisibilidadInicial | Perfil | ColorRGB | Rugosidad | Metallicidad | Referencia | Nota | Group | parentEquipmentId = Identificador del equipo padre | parentEquipmentName = Equipo padre | parentEquipmentIfcClass | parentEquipmentDimensions | parentEquipmentPositioning | parentEquipmentIssues | parentEquipmentDetail | componentRole = Rol del componente | assemblyBBox | assemblyGeometryMetrics | manufacturerDetailsPending | component | assembly | foundationRelationship | installationSourceScope | Identificador del elemento = sourcePartId | Componente | Capa de visualización | Estado del material | Perfil visual del material | Fuente del componente | Criterio de partición | Criterio de las dimensiones | Relación con cimentaciones | Aplicabilidad de las mediciones | Referencia dimensional del conjunto | sourceHandles | partCount | partsAreBOM | status
Compresor de aire AC1001C · Cuerpo de equipo · región CAD 26 | Componente de equipo · cuerpo o accesorio | Plano del fabricante: implantación de equipos · referencia E7 | 0.174581 | 0.280792 | 2.55 | 286.65 | 289.2 | 2.13483 | 0.094252 | Apoyo relativo +0.400 m; cero absoluto provisional | Componente de equipo · cuerpo o accesorio | equipmentComponent | {"name":"No especificado","source":"Sin especificación de material en la documentación revisada","status":"unknown"} | {"documented":[{"label":"Referencia dimensional del conjunto","value":"Plano general y dimensiones globales de AC1001C; no se asignan esas dimensiones globales a este componente.","unit":"","source":"EQ-IMPLANTACION-20260430 · LHD2609-GD01000 · espacio modelo","status":"referencia_del_conjunto"}],"geometry":[{"label":"Extensión de la malla en X","value":0.17458099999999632,"unit":"m","source":"Geometría releída del IFC; datum absoluto de proceso provisional","status":"derivado"},{"label":"Extensión de la malla en Y","value":0.28079200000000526,"unit":"m","source":"Geometría releída del IFC; datum absoluto de proceso provisional","status":"derivado"},{"label":"Extensión de la malla en Z","value":2.5500000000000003,"unit":"m","source":"Geometría releída del IFC; datum absoluto de proceso provisional","status":"derivado"},{"label":"Cota inferior de visualización","value":286.65,"unit":"m","source":"Geometría releída del IFC; datum absoluto de proceso provisional","status":"derivado"},{"label":"Cota superior de visualización","value":289.2,"unit":"m","source":"Geometría releída del IFC; datum absoluto de proceso provisional","status":"derivado"}],"notes":["Las dimensiones del equipo completo se conservan en parentEquipmentDimensions.","Las extensiones en X/Y son de los ejes del modelo y no sustituyen cotas locales de fabricación.","No se infieren espesores de chapa, tolerancias ni dimensiones de piezas a partir de la partición."]} | {"documentId":"EQ-IMPLANTACION-20260430","title":"Plano del fabricante: implantación de equipos","sheet":"LHD2609-GD01000 · espacio modelo","date":"2026-04-30","componentSourceHandles":["71A59","71DB1","71DB2","71DB5","72F0D","72F10","72F11"]} | {"horizontalStatus":"derivado_del_conjunto","verticalStatus":"derivado_del_conjunto","coordinateSystem":"model_local_m","parentEquipmentId":"AC1001C","transformApplied":false,"note":"Coordenadas copiadas exactamente del equipo coordinado; no se ha movido, girado, elevado ni reescalado este componente.","foundationRelationship":"El apoyo y las cotas de instalación se documentan para el conjunto padre. Esta submalla no acredita un anclaje directo.","meshMinimumAbsoluteElevationM":286.65,"assemblyPlacementField":"parentEquipmentPositioning"} | ["Componente separado de una reconstrucción documental del conjunto. Las alturas y detalles parciales conservan las limitaciones del fabricante registradas en parentEquipmentIssues.","Esta representación exterior no crea una chapa hueca ni añade componentes internos no documentados.","La pertenencia al conjunto no demuestra apoyo o anclaje directo a la cimentación."] | {"source":{"documentId":"EQ-IMPLANTACION-20260430","title":"Plano del fabricante: implantación de equipos","sheet":"LHD2609-GD01000 · espacio modelo","date":"2026-04-30","componentSourceHandles":["71A59","71DB1","71DB2","71DB5","72F0D","72F10","72F11"]},"sourcePartId":"AC1001C--cad-region-026","sourceHandles":["71A59","71DB1","71DB2","71DB5","72F0D","72F10","72F11"],"partCount":1,"partsAreBOM":false,"status":"Submalla exacta; interpretación funcional y cotas parciales provisionales."} | {"boundingBoxM":{"min":[63.308508,73.339928,1.65],"max":[63.483089,73.62072,4.2]},"extentsM":[0.174581,0.280792,2.55],"meshSurfaceM2":2.134829,"meshVolumeM3":0.094252,"closedSolid":true,"basis":"Geometría de coordinación. Los volúmenes de referencia y subcomponentes no son cantidades de material ni componentes de fabricación certificados."} | {"documentId":"LHD2609-JG00100-20260904","title":"Cimentaciones y pedestales de equipos · revisión recibida 04/09/2026","date":"2026-09-04","sheet":"1 / 1-1","sourceHandles":["28C35","28C38","28C3B","28C89"]} | equipment | {"id":"equipment","name":"Equipos"} | {"profileId":"equipment_light_gray","name":"Equipo · gris claro provisional","materialName":"No especificado","physicalMaterialStatus":"unknown","physicalMaterialSource":"Sin especificación de material en la documentación revisada","appearanceStatus":"provisional","appearanceBasis":"Referencia visual de fotografías públicas de Jinhong Gas / fabricante. Apariencia provisional para coordinación; fotografías oficiales pueden orientar el color, pero no acreditan el material, el acabado ni el equipo concreto.","appearanceReferences":["jinhong-official-asu"],"note":"El perfil visual no confirma material, grado ni acabado del componente."} | {"status":"componente_independiente","note":"Objeto independiente seleccionable. Las caras se asignan una sola vez entre todos los componentes del conjunto.","parentEquipmentId":"AC1001C","isAssemblyIdentityCarrier":false} | {"elementId":"AC1001C--cad-region-026","ifcGuid":"1MBnBLQgjNRhy70JW5cUEk","ifcClass":"IfcBuildingElementProxy","buildingId":"process_plant","buildingName":"Planta de proceso","sourceDocumentId":"EQ-IMPLANTACION-20260430","sourceRepresentationKind":"equipmentComponent"} | {"layerId":"equipment","layerName":"Equipos","role":"Componente de equipo · cuerpo o accesorio","basis":"Clasificación por función del elemento; no modifica las especificaciones documentales."} | {"profileId":"equipment_light_gray","name":"Equipo · gris claro provisional","status":"provisional","basis":"Referencia visual de fotografías públicas de Jinhong Gas / fabricante. Apariencia provisional para coordinación; fotografías oficiales pueden orientar el color, pero no acreditan el material, el acabado ni el equipo concreto.","physicalMaterialUnchanged":true} | Equipos | No especificado | Equipos | Equipo · gris claro provisional | provisional | AC1001C--cad-region-026 | ["Componente separado de una reconstrucción documental del conjunto. Las alturas y detalles parciales conservan las limitaciones del fabricante registradas en parentEquipmentIssues.","Esta representación exterior no crea una chapa hueca ni añade componentes internos no documentados.","La pertenencia al conjunto no demuestra apoyo o anclaje directo a la cimentación."] | Geometría de coordinación. Los volúmenes de referencia y subcomponentes no son cantidades de material ni componentes de fabricación certificados. | Sin especificación de material en la documentación revisada | {"documentId":"EQ-IMPLANTACION-20260430","title":"Plano del fabricante: implantación de equipos","sheet":"LHD2609-GD01000 · espacio modelo","date":"2026-04-30","componentSourceHandles":["71A59","71DB1","71DB2","71DB5","72F0D","72F10","72F11"]} | yes | equipment_light_gray | [0.88,0.89,0.88] | 0.45 | 0.28 | Referencia visual de fotografías públicas de Jinhong Gas / fabricante. Apariencia provisional para coordinación; fotografías oficiales pueden orientar el color, pero no acreditan el material, el acabado ni el equipo concreto. | La apariencia no certifica el material físico ni el acabado de fabricación. | BIM · Equipos | AC1001C | Compresor de aire AC1001C | IfcCompressor | {"documented":[{"label":"Dimensión X local del bastidor de referencia CAD","value":2.35,"unit":"m","source":"EQ-CARGAS-20260825 · contorno CAD · handles 3F0","status":"derivado"},{"label":"Dimensión Y local del bastidor de referencia CAD","value":5.22,"unit":"m","source":"EQ-CARGAS-20260825 · contorno CAD · handles 3F0","status":"derivado"},{"label":"Altura acotada","value":3.38,"unit":"m","source":"EQ-CARGAS-20260825 · handle 25AF","status":"documentado"},{"label":"Cota relativa de la superficie de apoyo","value":0.4,"unit":"m","source":"LHD2609-JG00100-20260904 · sección 1 / 1-1 · 28C35, 28C38, 28C3B, 28C89","status":"documentado"}],"geometry":[{"label":"Extensión de la malla en X","value":3.177584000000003,"unit":"m","source":"Geometría releída del IFC; datum absoluto de proceso provisional","status":"derivado"},{"label":"Extensión de la malla en Y","value":6.404527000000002,"unit":"m","source":"Geometría releída del IFC; datum absoluto de proceso provisional","status":"derivado"},{"label":"Extensión de la malla en Z","value":3.3800000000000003,"unit":"m","source":"Geometría releída del IFC; datum absoluto de proceso provisional","status":"derivado"},{"label":"Cota inferior de visualización","value":286.5,"unit":"m","source":"Geometría releída del IFC; datum absoluto de proceso provisional","status":"derivado"},{"label":"Cota superior de visualización","value":289.88,"unit":"m","source":"Geometría releída del IFC; datum absoluto de proceso provisional","status":"derivado"}],"notes":["Las extensiones de la malla se miden en los ejes del proyecto tras el giro de implantación; no sustituyen las dimensiones locales del fabricante.","La envolvente, su volumen y los espesores de visualización no son volúmenes de material ni cantidades de compra, construcción o fabricación.","Las dimensiones documentadas distinguen cotas explícitas y medidas extraídas de contornos CAD; las dimensiones geométricas describen únicamente la malla publicada.","Las extensiones de la malla refinada y las dimensiones documentadas del contorno o bastidor tienen distinto alcance; las cotas parciales del detalle son provisionales."]} | {"Estado de la planta":"Derivado del CAD y del giro de implantación","Nivel relativo del apoyo (m)":0.4,"Estado del nivel relativo":"Documentado en el plano de cimentaciones","Cero absoluto de visualización (m)":286.1,"Estado del cero absoluto":"Provisional","Cota del apoyo de visualización (m)":286.5,"Desplazamiento aplicado a la malla (m)":0.40000000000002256,"Criterio":"Nivel de apoyo relativo documentado. Se adopta el cero de proceso a 286,10 m solo para visualización; la equivalencia absoluta no está confirmada. No se añade un espesor de montaje sin cota del fabricante."} | ["La máquina está contenida en la envolvente de la cabina acústica; su superposición no acredita una interferencia física.","El bastidor CAD coincide con la referencia de 2,35 × 5,22 m del plano de cargas, pero cuerpos y auxiliares del detalle de abril sobresalen de esa referencia, hasta aproximadamente 1,048 m por el extremo sur y 0,246 m por el lado oeste. Extensión geométrica resultante: 2,595899 × 6,268101 × 3,38 m, derivada y pendiente de coordinación entre revisiones. Permanecen dentro de la cabina acústica. Compatibilidad de revisión pendiente de fabricante.","Todas las alturas parciales son hipótesis de visualización; solo la altura total de 3,38 m está acotada.","Las regiones del dibujo se usan como envolventes de cuerpos; la identificación funcional y la cota Z de cada pieza requieren verificación.","Pequeños taladros, tornillería y detalles interiores de las regiones no se extruyen como vacíos de fabricación.","El bastidor documentado mide 2,35 × 5,22 m. Los accesorios del detalle de abril sobresalen; el conjunto refinado ocupa aproximadamente 2,596 × 6,268 m en ejes del fabricante, pendiente de coordinación entre revisiones.","El acabado de grout HA-35 de 50 mm termina en +0,400; el hormigón termina en +0,350. La losa MAC contigua termina en +0,200.","El cero absoluto de la revisión no está definido; 286,10 m sigue siendo una hipótesis de coordinación.","Se alinea el punto inferior del conjunto del equipo, incluidos los pies ya representados, con la superficie de apoyo terminada; no se añade un espesor de calzos, placa o grout del fabricante no documentado."] | {"revision":"Detalle en planta de 2026-04-30 coordinado de forma preliminar con envolventes y alturas de 2026-08-25","status":"provisional","verticalRule":"Altura total documentada: 3,38 m. Plataforma gráfica de 0,15 m; los cuerpos extraídos de la planta reciben alturas provisionales entre 1,00 y 3,38 m, detalladas por subvolumen. No se dispone de alzado acotado de cada componente.","partCount":26,"source":{"documentId":"EQ-IMPLANTACION-20260430","title":"Plano del fabricante: implantación de equipos","sheet":"LHD2609-GD01000 · espacio modelo","date":"2026-04-30"},"heightSource":{"documentId":"EQ-CARGAS-20260825","title":"Plano del fabricante: cargas de equipos","sheet":"Espacio modelo","date":"2026-08-25"},"unconfirmedDimensions":["Todas las alturas parciales son hipótesis de visualización; solo la altura total de 3,38 m está acotada.","Las regiones del dibujo se usan como envolventes de cuerpos; la identificación funcional y la cota Z de cada pieza requieren verificación.","Pequeños taladros, tornillería y detalles interiores de las regiones no se extruyen como vacíos de fabricación."],"quantityUse":"Magnitudes de la geometría representada; no son cantidades de material, obra, compra, capacidad útil ni fabricación. En geometrías compuestas se suman superficies y volúmenes de partes y pueden existir solapes no depurados.","partsAreBOM":false} | equipment_component | {"min":[60.820401,68.378413,1.5],"max":[63.997985,74.78294,4.88]} | {"boundingBoxM":{"min":[60.820401,68.378413,1.5],"max":[63.997985,74.78294,4.88]},"extentsM":[3.177584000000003,6.404527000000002,3.38],"meshSurfaceM2":165.19823143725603,"meshVolumeM3":20.170106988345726,"closedSolid":true,"windingConsistent":true,"basis":"Submalla exacta de los triángulos del modelo IFC coordinado; separación de componentes sin transformación ni retesselación."} | ["Todas las alturas parciales son hipótesis de visualización; solo la altura total de 3,38 m está acotada.","Las regiones del dibujo se usan como envolventes de cuerpos; la identificación funcional y la cota Z de cada pieza requieren verificación.","Pequeños taladros, tornillería y detalles interiores de las regiones no se extruyen como vacíos de fabricación.","La separación gráfica no aporta cotas de fabricación ni identifica piezas internas no documentadas.","Los materiales y acabados permanecen provisionales; las fotografías públicas solo orientan la apariencia."] | {"id":"AC1001C--cad-region-026","sourcePartId":"AC1001C--cad-region-026","name":"Cuerpo de equipo · región CAD 26","role":"equipment_component","classificationStatus":"provisional","classificationBasis":"Rol del subvolumen gráfico según el activo de detalle; identidad de fabricación no confirmada.","parentEquipmentId":"AC1001C","parentEquipmentGuid":"2IJ0PLLizIvfouRXAkczXf","isAssemblyIdentityCarrier":false,"sourceFaceRange":[1696,1708],"sourceCurrentFaceIndices":[1696,1697,1698,1699,1700,1701,1702,1703,1704,1705,1706,1707],"sourceMeshSha256":"7b60c904c9d84d22fded9be34af09a09a9c198ec8e75e61902634d5e4064c761","sourceVertexIndices":[890,891,892,893,894,895,896,897],"separationMethod":"Partición exacta de triángulos existentes; coordenadas y orientación de caras conservadas.","quantityUse":"Magnitudes geométricas del subvolumen; no son cantidades netas de material, fabricación, suministro o capacidad."} | {"id":"AC1001C","name":"Compresor de aire AC1001C","relationship":"decomposed_component","parentShapeMeaning":"La forma del objeto que conserva el ID del equipo es únicamente su componente principal; el conjunto completo requiere sus hijos."} | {"kind":"through_parent","parentEquipmentId":"AC1001C","directAnchorageVerified":false,"note":"La relación del conjunto con cimentaciones se conserva en el objeto que mantiene el ID del equipo; no se atribuye fijación directa a cada subcomponente."} | Documento de implantación y apoyo del conjunto padre; no acredita fijación individual de este componente. | AC1001C--cad-region-026 | Cuerpo de equipo · región CAD 26 | Equipos | unknown | equipment_light_gray | {"documentId":"EQ-IMPLANTACION-20260430","title":"Plano del fabricante: implantación de equipos","sheet":"LHD2609-GD01000 · espacio modelo","date":"2026-04-30","componentSourceHandles":["71A59","71DB1","71DB2","71DB5","72F0D","72F10","72F11"]} | Submalla de triángulos existentes; no hay nueva posición ni nuevas caras. | Cotas globales del conjunto conservadas aparte; las dimensiones de esta ficha son de la submalla. | Coordinación del conjunto padre; anclaje directo individual no acreditado. | Superficie y volumen geométricos brutos; no constituyen cantidades netas de obra, material o fabricación. | Plano general y dimensiones globales de AC1001C; no se asignan esas dimensiones globales a este componente. | ["71A59","71DB1","71DB2","71DB5","72F0D","72F10","72F11"] | 1 | no | Submalla exacta; interpretación funcional y cotas parciales provisionales.
Compresor de aire AC1001C · Cuerpo de equipo · región CAD 27 | Componente de equipo · cuerpo o accesorio | Plano del fabricante: implantación de equipos · referencia E7 | 0.374455 | 0.235633 | 2.2 | 286.65 | 288.85 | 2.5781 | 0.077277 | Apoyo relativo +0.400 m; cero absoluto provisional | Componente de equipo · cuerpo o accesorio | equipmentComponent | {"name":"No especificado","source":"Sin especificación de material en la documentación revisada","status":"unknown"} | {"documented":[{"label":"Referencia dimensional del conjunto","value":"Plano general y dimensiones globales de AC1001C; no se asignan esas dimensiones globales a este componente.","unit":"","source":"EQ-IMPLANTACION-20260430 · LHD2609-GD01000 · espacio modelo","status":"referencia_del_conjunto"}],"geometry":[{"label":"Extensión de la malla en X","value":0.37445499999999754,"unit":"m","source":"Geometría releída del IFC; datum absoluto de proceso provisional","status":"derivado"},{"label":"Extensión de la malla en Y","value":0.23563299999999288,"unit":"m","source":"Geometría releída del IFC; datum absoluto de proceso provisional","status":"derivado"},{"label":"Extensión de la malla en Z","value":2.2,"unit":"m","source":"Geometría releída del IFC; datum absoluto de proceso provisional","status":"derivado"},{"label":"Cota inferior de visualización","value":286.65,"unit":"m","source":"Geometría releída del IFC; datum absoluto de proceso provisional","status":"derivado"},{"label":"Cota superior de visualización","value":288.85,"unit":"m","source":"Geometría releída del IFC; datum absoluto de proceso provisional","status":"derivado"}],"notes":["Las dimensiones del equipo completo se conservan en parentEquipmentDimensions.","Las extensiones en X/Y son de los ejes del modelo y no sustituyen cotas locales de fabricación.","No se infieren espesores de chapa, tolerancias ni dimensiones de piezas a partir de la partición."]} | {"documentId":"EQ-IMPLANTACION-20260430","title":"Plano del fabricante: implantación de equipos","sheet":"LHD2609-GD01000 · espacio modelo","date":"2026-04-30","componentSourceHandles":["71743","71744","71745","71746","71749","71753","71754","7175F","71760","717A8","717AB","717F4","7181D","7181E","71828","71829","7182F","71832","71833","718C5","718C9","719CA","719CC","71A2F","71A44","71DB9","73148","73153","73154","7344E"]} | {"horizontalStatus":"derivado_del_conjunto","verticalStatus":"derivado_del_conjunto","coordinateSystem":"model_local_m","parentEquipmentId":"AC1001C","transformApplied":false,"note":"Coordenadas copiadas exactamente del equipo coordinado; no se ha movido, girado, elevado ni reescalado este componente.","foundationRelationship":"El apoyo y las cotas de instalación se documentan para el conjunto padre. Esta submalla no acredita un anclaje directo.","meshMinimumAbsoluteElevationM":286.65,"assemblyPlacementField":"parentEquipmentPositioning"} | ["Componente separado de una reconstrucción documental del conjunto. Las alturas y detalles parciales conservan las limitaciones del fabricante registradas en parentEquipmentIssues.","Esta representación exterior no crea una chapa hueca ni añade componentes internos no documentados.","La pertenencia al conjunto no demuestra apoyo o anclaje directo a la cimentación."] | {"source":{"documentId":"EQ-IMPLANTACION-20260430","title":"Plano del fabricante: implantación de equipos","sheet":"LHD2609-GD01000 · espacio modelo","date":"2026-04-30","componentSourceHandles":["71743","71744","71745","71746","71749","71753","71754","7175F","71760","717A8","717AB","717F4","7181D","7181E","71828","71829","7182F","71832","71833","718C5","718C9","719CA","719CC","71A2F","71A44","71DB9","73148","73153","73154","7344E"]},"sourcePartId":"AC1001C--cad-region-027","sourceHandles":["71743","71744","71745","71746","71749","71753","71754","7175F","71760","717A8","717AB","717F4","7181D","7181E","71828","71829","7182F","71832","71833","718C5","718C9","719CA","719CC","71A2F","71A44","71DB9","73148","73153","73154","7344E"],"partCount":1,"partsAreBOM":false,"status":"Submalla exacta; interpretación funcional y cotas parciales provisionales."} | {"boundingBoxM":{"min":[63.243467,72.855568,1.65],"max":[63.617922,73.091201,3.85]},"extentsM":[0.374455,0.235633,2.2],"meshSurfaceM2":2.578097,"meshVolumeM3":0.077277,"closedSolid":true,"basis":"Geometría de coordinación. Los volúmenes de referencia y subcomponentes no son cantidades de material ni componentes de fabricación certificados."} | {"documentId":"LHD2609-JG00100-20260904","title":"Cimentaciones y pedestales de equipos · revisión recibida 04/09/2026","date":"2026-09-04","sheet":"1 / 1-1","sourceHandles":["28C35","28C38","28C3B","28C89"]} | equipment | {"id":"equipment","name":"Equipos"} | {"profileId":"equipment_light_gray","name":"Equipo · gris claro provisional","materialName":"No especificado","physicalMaterialStatus":"unknown","physicalMaterialSource":"Sin especificación de material en la documentación revisada","appearanceStatus":"provisional","appearanceBasis":"Referencia visual de fotografías públicas de Jinhong Gas / fabricante. Apariencia provisional para coordinación; fotografías oficiales pueden orientar el color, pero no acreditan el material, el acabado ni el equipo concreto.","appearanceReferences":["jinhong-official-asu"],"note":"El perfil visual no confirma material, grado ni acabado del componente."} | {"status":"componente_independiente","note":"Objeto independiente seleccionable. Las caras se asignan una sola vez entre todos los componentes del conjunto.","parentEquipmentId":"AC1001C","isAssemblyIdentityCarrier":false} | {"elementId":"AC1001C--cad-region-027","ifcGuid":"2NB4T1DHDNZwmUfXckG_zV","ifcClass":"IfcBuildingElementProxy","buildingId":"process_plant","buildingName":"Planta de proceso","sourceDocumentId":"EQ-IMPLANTACION-20260430","sourceRepresentationKind":"equipmentComponent"} | {"layerId":"equipment","layerName":"Equipos","role":"Componente de equipo · cuerpo o accesorio","basis":"Clasificación por función del elemento; no modifica las especificaciones documentales."} | {"profileId":"equipment_light_gray","name":"Equipo · gris claro provisional","status":"provisional","basis":"Referencia visual de fotografías públicas de Jinhong Gas / fabricante. Apariencia provisional para coordinación; fotografías oficiales pueden orientar el color, pero no acreditan el material, el acabado ni el equipo concreto.","physicalMaterialUnchanged":true} | Equipos | No especificado | Equipos | Equipo · gris claro provisional | provisional | AC1001C--cad-region-027 | ["Componente separado de una reconstrucción documental del conjunto. Las alturas y detalles parciales conservan las limitaciones del fabricante registradas en parentEquipmentIssues.","Esta representación exterior no crea una chapa hueca ni añade componentes internos no documentados.","La pertenencia al conjunto no demuestra apoyo o anclaje directo a la cimentación."] | Geometría de coordinación. Los volúmenes de referencia y subcomponentes no son cantidades de material ni componentes de fabricación certificados. | Sin especificación de material en la documentación revisada | {"documentId":"EQ-IMPLANTACION-20260430","title":"Plano del fabricante: implantación de equipos","sheet":"LHD2609-GD01000 · espacio modelo","date":"2026-04-30","componentSourceHandles":["71743","71744","71745","71746","71749","71753","71754","7175F","71760","717A8","717AB","717F4","7181D","7181E","71828","71829","7182F","71832","71833","718C5","718C9","719CA","719CC","71A2F","71A44","71DB9","73148","73153","73154","7344E"]} | yes | equipment_light_gray | [0.88,0.89,0.88] | 0.45 | 0.28 | Referencia visual de fotografías públicas de Jinhong Gas / fabricante. Apariencia provisional para coordinación; fotografías oficiales pueden orientar el color, pero no acreditan el material, el acabado ni el equipo concreto. | La apariencia no certifica el material físico ni el acabado de fabricación. | BIM · Equipos | AC1001C | Compresor de aire AC1001C | IfcCompressor | {"documented":[{"label":"Dimensión X local del bastidor de referencia CAD","value":2.35,"unit":"m","source":"EQ-CARGAS-20260825 · contorno CAD · handles 3F0","status":"derivado"},{"label":"Dimensión Y local del bastidor de referencia CAD","value":5.22,"unit":"m","source":"EQ-CARGAS-20260825 · contorno CAD · handles 3F0","status":"derivado"},{"label":"Altura acotada","value":3.38,"unit":"m","source":"EQ-CARGAS-20260825 · handle 25AF","status":"documentado"},{"label":"Cota relativa de la superficie de apoyo","value":0.4,"unit":"m","source":"LHD2609-JG00100-20260904 · sección 1 / 1-1 · 28C35, 28C38, 28C3B, 28C89","status":"documentado"}],"geometry":[{"label":"Extensión de la malla en X","value":3.177584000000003,"unit":"m","source":"Geometría releída del IFC; datum absoluto de proceso provisional","status":"derivado"},{"label":"Extensión de la malla en Y","value":6.404527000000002,"unit":"m","source":"Geometría releída del IFC; datum absoluto de proceso provisional","status":"derivado"},{"label":"Extensión de la malla en Z","value":3.3800000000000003,"unit":"m","source":"Geometría releída del IFC; datum absoluto de proceso provisional","status":"derivado"},{"label":"Cota inferior de visualización","value":286.5,"unit":"m","source":"Geometría releída del IFC; datum absoluto de proceso provisional","status":"derivado"},{"label":"Cota superior de visualización","value":289.88,"unit":"m","source":"Geometría releída del IFC; datum absoluto de proceso provisional","status":"derivado"}],"notes":["Las extensiones de la malla se miden en los ejes del proyecto tras el giro de implantación; no sustituyen las dimensiones locales del fabricante.","La envolvente, su volumen y los espesores de visualización no son volúmenes de material ni cantidades de compra, construcción o fabricación.","Las dimensiones documentadas distinguen cotas explícitas y medidas extraídas de contornos CAD; las dimensiones geométricas describen únicamente la malla publicada.","Las extensiones de la malla refinada y las dimensiones documentadas del contorno o bastidor tienen distinto alcance; las cotas parciales del detalle son provisionales."]} | {"Estado de la planta":"Derivado del CAD y del giro de implantación","Nivel relativo del apoyo (m)":0.4,"Estado del nivel relativo":"Documentado en el plano de cimentaciones","Cero absoluto de visualización (m)":286.1,"Estado del cero absoluto":"Provisional","Cota del apoyo de visualización (m)":286.5,"Desplazamiento aplicado a la malla (m)":0.40000000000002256,"Criterio":"Nivel de apoyo relativo documentado. Se adopta el cero de proceso a 286,10 m solo para visualización; la equivalencia absoluta no está confirmada. No se añade un espesor de montaje sin cota del fabricante."} | ["La máquina está contenida en la envolvente de la cabina acústica; su superposición no acredita una interferencia física.","El bastidor CAD coincide con la referencia de 2,35 × 5,22 m del plano de cargas, pero cuerpos y auxiliares del detalle de abril sobresalen de esa referencia, hasta aproximadamente 1,048 m por el extremo sur y 0,246 m por el lado oeste. Extensión geométrica resultante: 2,595899 × 6,268101 × 3,38 m, derivada y pendiente de coordinación entre revisiones. Permanecen dentro de la cabina acústica. Compatibilidad de revisión pendiente de fabricante.","Todas las alturas parciales son hipótesis de visualización; solo la altura total de 3,38 m está acotada.","Las regiones del dibujo se usan como envolventes de cuerpos; la identificación funcional y la cota Z de cada pieza requieren verificación.","Pequeños taladros, tornillería y detalles interiores de las regiones no se extruyen como vacíos de fabricación.","El bastidor documentado mide 2,35 × 5,22 m. Los accesorios del detalle de abril sobresalen; el conjunto refinado ocupa aproximadamente 2,596 × 6,268 m en ejes del fabricante, pendiente de coordinación entre revisiones.","El acabado de grout HA-35 de 50 mm termina en +0,400; el hormigón termina en +0,350. La losa MAC contigua termina en +0,200.","El cero absoluto de la revisión no está definido; 286,10 m sigue siendo una hipótesis de coordinación.","Se alinea el punto inferior del conjunto del equipo, incluidos los pies ya representados, con la superficie de apoyo terminada; no se añade un espesor de calzos, placa o grout del fabricante no documentado."] | {"revision":"Detalle en planta de 2026-04-30 coordinado de forma preliminar con envolventes y alturas de 2026-08-25","status":"provisional","verticalRule":"Altura total documentada: 3,38 m. Plataforma gráfica de 0,15 m; los cuerpos extraídos de la planta reciben alturas provisionales entre 1,00 y 3,38 m, detalladas por subvolumen. No se dispone de alzado acotado de cada componente.","partCount":26,"source":{"documentId":"EQ-IMPLANTACION-20260430","title":"Plano del fabricante: implantación de equipos","sheet":"LHD2609-GD01000 · espacio modelo","date":"2026-04-30"},"heightSource":{"documentId":"EQ-CARGAS-20260825","title":"Plano del fabricante: cargas de equipos","sheet":"Espacio modelo","date":"2026-08-25"},"unconfirmedDimensions":["Todas las alturas parciales son hipótesis de visualización; solo la altura total de 3,38 m está acotada.","Las regiones del dibujo se usan como envolventes de cuerpos; la identificación funcional y la cota Z de cada pieza requieren verificación.","Pequeños taladros, tornillería y detalles interiores de las regiones no se extruyen como vacíos de fabricación."],"quantityUse":"Magnitudes de la geometría representada; no son cantidades de material, obra, compra, capacidad útil ni fabricación. En geometrías compuestas se suman superficies y volúmenes de partes y pueden existir solapes no depurados.","partsAreBOM":false} | equipment_component | {"min":[60.820401,68.378413,1.5],"max":[63.997985,74.78294,4.88]} | {"boundingBoxM":{"min":[60.820401,68.378413,1.5],"max":[63.997985,74.78294,4.88]},"extentsM":[3.177584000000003,6.404527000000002,3.38],"meshSurfaceM2":165.19823143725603,"meshVolumeM3":20.170106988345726,"closedSolid":true,"windingConsistent":true,"basis":"Submalla exacta de los triángulos del modelo IFC coordinado; separación de componentes sin transformación ni retesselación."} | ["Todas las alturas parciales son hipótesis de visualización; solo la altura total de 3,38 m está acotada.","Las regiones del dibujo se usan como envolventes de cuerpos; la identificación funcional y la cota Z de cada pieza requieren verificación.","Pequeños taladros, tornillería y detalles interiores de las regiones no se extruyen como vacíos de fabricación.","La separación gráfica no aporta cotas de fabricación ni identifica piezas internas no documentadas.","Los materiales y acabados permanecen provisionales; las fotografías públicas solo orientan la apariencia."] | {"id":"AC1001C--cad-region-027","sourcePartId":"AC1001C--cad-region-027","name":"Cuerpo de equipo · región CAD 27","role":"equipment_component","classificationStatus":"provisional","classificationBasis":"Rol del subvolumen gráfico según el activo de detalle; identidad de fabricación no confirmada.","parentEquipmentId":"AC1001C","parentEquipmentGuid":"2IJ0PLLizIvfouRXAkczXf","isAssemblyIdentityCarrier":false,"sourceFaceRange":[1708,1776],"sourceCurrentFaceIndices":[1708,1709,1710,1711,1712,1713,1714,1715,1716,1717,1718,1719,1720,1721,1722,1723,1724,1725,1726,1727,1728,1729,1730,1731,1732,1733,1734,1735,1736,1737,1738,1739,1740,1741,1742,1743,1744,1745,1746,1747,1748,1749,1750,1751,1752,1753,1754,1755,1756,1757,1758,1759,1760,1761,1762,1763,1764,1765,1766,1767,1768,1769,1770,1771,1772,1773,1774,1775],"sourceMeshSha256":"7b60c904c9d84d22fded9be34af09a09a9c198ec8e75e61902634d5e4064c761","sourceVertexIndices":[898,899,900,901,902,903,904,905,906,907,908,909,910,911,912,913,914,915,916,917,918,919,920,921,922,923,924,925,926,927,928,929,930,931,932,933],"separationMethod":"Partición exacta de triángulos existentes; coordenadas y orientación de caras conservadas.","quantityUse":"Magnitudes geométricas del subvolumen; no son cantidades netas de material, fabricación, suministro o capacidad."} | {"id":"AC1001C","name":"Compresor de aire AC1001C","relationship":"decomposed_component","parentShapeMeaning":"La forma del objeto que conserva el ID del equipo es únicamente su componente principal; el conjunto completo requiere sus hijos."} | {"kind":"through_parent","parentEquipmentId":"AC1001C","directAnchorageVerified":false,"note":"La relación del conjunto con cimentaciones se conserva en el objeto que mantiene el ID del equipo; no se atribuye fijación directa a cada subcomponente."} | Documento de implantación y apoyo del conjunto padre; no acredita fijación individual de este componente. | AC1001C--cad-region-027 | Cuerpo de equipo · región CAD 27 | Equipos | unknown | equipment_light_gray | {"documentId":"EQ-IMPLANTACION-20260430","title":"Plano del fabricante: implantación de equipos","sheet":"LHD2609-GD01000 · espacio modelo","date":"2026-04-30","componentSourceHandles":["71743","71744","71745","71746","71749","71753","71754","7175F","71760","717A8","717AB","717F4","7181D","7181E","71828","71829","7182F","71832","71833","718C5","718C9","719CA","719CC","71A2F","71A44","71DB9","73148","73153","73154","7344E"]} | Submalla de triángulos existentes; no hay nueva posición ni nuevas caras. | Cotas globales del conjunto conservadas aparte; las dimensiones de esta ficha son de la submalla. | Coordinación del conjunto padre; anclaje directo individual no acreditado. | Superficie y volumen geométricos brutos; no constituyen cantidades netas de obra, material o fabricación. | Plano general y dimensiones globales de AC1001C; no se asignan esas dimensiones globales a este componente. | ["71743","71744","71745","71746","71749","71753","71754","7175F","71760","717A8","717AB","717F4","7181D","7181E","71828","71829","7182F","71832","71833","718C5","718C9","719CA","719CC","71A2F","71A44","71DB9","73148","73153","73154","7344E"] | 1 | no | Submalla exacta; interpretación funcional y cotas parciales provisionales.
Compresor de aire AC1001C · Cuerpo de equipo · región CAD 28 | Componente de equipo · cuerpo o accesorio | Plano del fabricante: implantación de equipos · referencia E7 | 0.388733 | 0.307071 | 2.35 | 286.65 | 289 | 4.9401 | 0.081169 | Apoyo relativo +0.400 m; cero absoluto provisional | Componente de equipo · cuerpo o accesorio | equipmentComponent | {"name":"No especificado","source":"Sin especificación de material en la documentación revisada","status":"unknown"} | {"documented":[{"label":"Referencia dimensional del conjunto","value":"Plano general y dimensiones globales de AC1001C; no se asignan esas dimensiones globales a este componente.","unit":"","source":"EQ-IMPLANTACION-20260430 · LHD2609-GD01000 · espacio modelo","status":"referencia_del_conjunto"}],"geometry":[{"label":"Extensión de la malla en X","value":0.388733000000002,"unit":"m","source":"Geometría releída del IFC; datum absoluto de proceso provisional","status":"derivado"},{"label":"Extensión de la malla en Y","value":0.30707100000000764,"unit":"m","source":"Geometría releída del IFC; datum absoluto de proceso provisional","status":"derivado"},{"label":"Extensión de la malla en Z","value":2.35,"unit":"m","source":"Geometría releída del IFC; datum absoluto de proceso provisional","status":"derivado"},{"label":"Cota inferior de visualización","value":286.65,"unit":"m","source":"Geometría releída del IFC; datum absoluto de proceso provisional","status":"derivado"},{"label":"Cota superior de visualización","value":289.0,"unit":"m","source":"Geometría releída del IFC; datum absoluto de proceso provisional","status":"derivado"}],"notes":["Las dimensiones del equipo completo se conservan en parentEquipmentDimensions.","Las extensiones en X/Y son de los ejes del modelo y no sustituyen cotas locales de fabricación.","No se infieren espesores de chapa, tolerancias ni dimensiones de piezas a partir de la partición."]} | {"documentId":"EQ-IMPLANTACION-20260430","title":"Plano del fabricante: implantación de equipos","sheet":"LHD2609-GD01000 · espacio modelo","date":"2026-04-30","componentSourceHandles":["717FF","71801","71803","71805","71A46","71A58","71A59","71BA6","71BA7","71DB1","71DB2","71DB4","71DB5","72EE3","72EE5","72EE6","72EEA","72EEB","72EEF","72EF0","72EF3","72EF4","72EF6","72F00","72F01","72F02","72F0D","72F0E","72F0F","72F11","73157","73158","73159","7315A","7315B","7315C","731BD","731C4","731C5","731C7","731CB","731CC","731CD","731D9","731DE","731DF","731E0","731E1","731E2","731E3","731E4","731E5","731E6","731EE","731EF","731F0","731F1","731F2","731F3","731F4","731F5","731F6","731F7","731F9","731FF","73200","73201","73202","73204","73205","73206","73207","7320B","7320D","7320E","7320F","73210","73212","7321C","7321D"]} | {"horizontalStatus":"derivado_del_conjunto","verticalStatus":"derivado_del_conjunto","coordinateSystem":"model_local_m","parentEquipmentId":"AC1001C","transformApplied":false,"note":"Coordenadas copiadas exactamente del equipo coordinado; no se ha movido, girado, elevado ni reescalado este componente.","foundationRelationship":"El apoyo y las cotas de instalación se documentan para el conjunto padre. Esta submalla no acredita un anclaje directo.","meshMinimumAbsoluteElevationM":286.65,"assemblyPlacementField":"parentEquipmentPositioning"} | ["Componente separado de una reconstrucción documental del conjunto. Las alturas y detalles parciales conservan las limitaciones del fabricante registradas en parentEquipmentIssues.","Esta representación exterior no crea una chapa hueca ni añade componentes internos no documentados.","La pertenencia al conjunto no demuestra apoyo o anclaje directo a la cimentación."] | {"source":{"documentId":"EQ-IMPLANTACION-20260430","title":"Plano del fabricante: implantación de equipos","sheet":"LHD2609-GD01000 · espacio modelo","date":"2026-04-30","componentSourceHandles":["717FF","71801","71803","71805","71A46","71A58","71A59","71BA6","71BA7","71DB1","71DB2","71DB4","71DB5","72EE3","72EE5","72EE6","72EEA","72EEB","72EEF","72EF0","72EF3","72EF4","72EF6","72F00","72F01","72F02","72F0D","72F0E","72F0F","72F11","73157","73158","73159","7315A","7315B","7315C","731BD","731C4","731C5","731C7","731CB","731CC","731CD","731D9","731DE","731DF","731E0","731E1","731E2","731E3","731E4","731E5","731E6","731EE","731EF","731F0","731F1","731F2","731F3","731F4","731F5","731F6","731F7","731F9","731FF","73200","73201","73202","73204","73205","73206","73207","7320B","7320D","7320E","7320F","73210","73212","7321C","7321D"]},"sourcePartId":"AC1001C--cad-region-028","sourceHandles":["717FF","71801","71803","71805","71A46","71A58","71A59","71BA6","71BA7","71DB1","71DB2","71DB4","71DB5","72EE3","72EE5","72EE6","72EEA","72EEB","72EEF","72EF0","72EF3","72EF4","72EF6","72F00","72F01","72F02","72F0D","72F0E","72F0F","72F11","73157","73158","73159","7315A","7315B","7315C","731BD","731C4","731C5","731C7","731CB","731CC","731CD","731D9","731DE","731DF","731E0","731E1","731E2","731E3","731E4","731E5","731E6","731EE","731EF","731F0","731F1","731F2","731F3","731F4","731F5","731F6","731F7","731F9","731FF","73200","73201","73202","73204","73205","73206","73207","7320B","7320D","7320E","7320F","73210","73212","7321C","7321D"],"partCount":1,"partsAreBOM":false,"status":"Submalla exacta; interpretación funcional y cotas parciales provisionales."} | {"boundingBoxM":{"min":[63.156999,73.175812,1.65],"max":[63.545732,73.482883,4.0]},"extentsM":[0.388733,0.307071,2.35],"meshSurfaceM2":4.940102,"meshVolumeM3":0.081169,"closedSolid":true,"basis":"Geometría de coordinación. Los volúmenes de referencia y subcomponentes no son cantidades de material ni componentes de fabricación certificados."} | {"documentId":"LHD2609-JG00100-20260904","title":"Cimentaciones y pedestales de equipos · revisión recibida 04/09/2026","date":"2026-09-04","sheet":"1 / 1-1","sourceHandles":["28C35","28C38","28C3B","28C89"]} | equipment | {"id":"equipment","name":"Equipos"} | {"profileId":"equipment_light_gray","name":"Equipo · gris claro provisional","materialName":"No especificado","physicalMaterialStatus":"unknown","physicalMaterialSource":"Sin especificación de material en la documentación revisada","appearanceStatus":"provisional","appearanceBasis":"Referencia visual de fotografías públicas de Jinhong Gas / fabricante. Apariencia provisional para coordinación; fotografías oficiales pueden orientar el color, pero no acreditan el material, el acabado ni el equipo concreto.","appearanceReferences":["jinhong-official-asu"],"note":"El perfil visual no confirma material, grado ni acabado del componente."} | {"status":"componente_independiente","note":"Objeto independiente seleccionable. Las caras se asignan una sola vez entre todos los componentes del conjunto.","parentEquipmentId":"AC1001C","isAssemblyIdentityCarrier":false} | {"elementId":"AC1001C--cad-region-028","ifcGuid":"2e6pqSCA1GoxxNEyUuPO5w","ifcClass":"IfcBuildingElementProxy","buildingId":"process_plant","buildingName":"Planta de proceso","sourceDocumentId":"EQ-IMPLANTACION-20260430","sourceRepresentationKind":"equipmentComponent"} | {"layerId":"equipment","layerName":"Equipos","role":"Componente de equipo · cuerpo o accesorio","basis":"Clasificación por función del elemento; no modifica las especificaciones documentales."} | {"profileId":"equipment_light_gray","name":"Equipo · gris claro provisional","status":"provisional","basis":"Referencia visual de fotografías públicas de Jinhong Gas / fabricante. Apariencia provisional para coordinación; fotografías oficiales pueden orientar el color, pero no acreditan el material, el acabado ni el equipo concreto.","physicalMaterialUnchanged":true} | Equipos | No especificado | Equipos | Equipo · gris claro provisional | provisional | AC1001C--cad-region-028 | ["Componente separado de una reconstrucción documental del conjunto. Las alturas y detalles parciales conservan las limitaciones del fabricante registradas en parentEquipmentIssues.","Esta representación exterior no crea una chapa hueca ni añade componentes internos no documentados.","La pertenencia al conjunto no demuestra apoyo o anclaje directo a la cimentación."] | Geometría de coordinación. Los volúmenes de referencia y subcomponentes no son cantidades de material ni componentes de fabricación certificados. | Sin especificación de material en la documentación revisada | {"documentId":"EQ-IMPLANTACION-20260430","title":"Plano del fabricante: implantación de equipos","sheet":"LHD2609-GD01000 · espacio modelo","date":"2026-04-30","componentSourceHandles":["717FF","71801","71803","71805","71A46","71A58","71A59","71BA6","71BA7","71DB1","71DB2","71DB4","71DB5","72EE3","72EE5","72EE6","72EEA","72EEB","72EEF","72EF0","72EF3","72EF4","72EF6","72F00","72F01","72F02","72F0D","72F0E","72F0F","72F11","73157","73158","73159","7315A","7315B","7315C","731BD","731C4","731C5","731C7","731CB","731CC","731CD","731D9","731DE","731DF","731E0","731E1","731E2","731E3","731E4","731E5","731E6","731EE","731EF","731F0","731F1","731F2","731F3","731F4","731F5","731F6","731F7","731F9","731FF","73200","73201","73202","73204","73205","73206","73207","7320B","7320D","7320E","7320F","73210","73212","7321C","7321D"]} | yes | equipment_light_gray | [0.88,0.89,0.88] | 0.45 | 0.28 | Referencia visual de fotografías públicas de Jinhong Gas / fabricante. Apariencia provisional para coordinación; fotografías oficiales pueden orientar el color, pero no acreditan el material, el acabado ni el equipo concreto. | La apariencia no certifica el material físico ni el acabado de fabricación. | BIM · Equipos | AC1001C | Compresor de aire AC1001C | IfcCompressor | {"documented":[{"label":"Dimensión X local del bastidor de referencia CAD","value":2.35,"unit":"m","source":"EQ-CARGAS-20260825 · contorno CAD · handles 3F0","status":"derivado"},{"label":"Dimensión Y local del bastidor de referencia CAD","value":5.22,"unit":"m","source":"EQ-CARGAS-20260825 · contorno CAD · handles 3F0","status":"derivado"},{"label":"Altura acotada","value":3.38,"unit":"m","source":"EQ-CARGAS-20260825 · handle 25AF","status":"documentado"},{"label":"Cota relativa de la superficie de apoyo","value":0.4,"unit":"m","source":"LHD2609-JG00100-20260904 · sección 1 / 1-1 · 28C35, 28C38, 28C3B, 28C89","status":"documentado"}],"geometry":[{"label":"Extensión de la malla en X","value":3.177584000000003,"unit":"m","source":"Geometría releída del IFC; datum absoluto de proceso provisional","status":"derivado"},{"label":"Extensión de la malla en Y","value":6.404527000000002,"unit":"m","source":"Geometría releída del IFC; datum absoluto de proceso provisional","status":"derivado"},{"label":"Extensión de la malla en Z","value":3.3800000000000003,"unit":"m","source":"Geometría releída del IFC; datum absoluto de proceso provisional","status":"derivado"},{"label":"Cota inferior de visualización","value":286.5,"unit":"m","source":"Geometría releída del IFC; datum absoluto de proceso provisional","status":"derivado"},{"label":"Cota superior de visualización","value":289.88,"unit":"m","source":"Geometría releída del IFC; datum absoluto de proceso provisional","status":"derivado"}],"notes":["Las extensiones de la malla se miden en los ejes del proyecto tras el giro de implantación; no sustituyen las dimensiones locales del fabricante.","La envolvente, su volumen y los espesores de visualización no son volúmenes de material ni cantidades de compra, construcción o fabricación.","Las dimensiones documentadas distinguen cotas explícitas y medidas extraídas de contornos CAD; las dimensiones geométricas describen únicamente la malla publicada.","Las extensiones de la malla refinada y las dimensiones documentadas del contorno o bastidor tienen distinto alcance; las cotas parciales del detalle son provisionales."]} | {"Estado de la planta":"Derivado del CAD y del giro de implantación","Nivel relativo del apoyo (m)":0.4,"Estado del nivel relativo":"Documentado en el plano de cimentaciones","Cero absoluto de visualización (m)":286.1,"Estado del cero absoluto":"Provisional","Cota del apoyo de visualización (m)":286.5,"Desplazamiento aplicado a la malla (m)":0.40000000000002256,"Criterio":"Nivel de apoyo relativo documentado. Se adopta el cero de proceso a 286,10 m solo para visualización; la equivalencia absoluta no está confirmada. No se añade un espesor de montaje sin cota del fabricante."} | ["La máquina está contenida en la envolvente de la cabina acústica; su superposición no acredita una interferencia física.","El bastidor CAD coincide con la referencia de 2,35 × 5,22 m del plano de cargas, pero cuerpos y auxiliares del detalle de abril sobresalen de esa referencia, hasta aproximadamente 1,048 m por el extremo sur y 0,246 m por el lado oeste. Extensión geométrica resultante: 2,595899 × 6,268101 × 3,38 m, derivada y pendiente de coordinación entre revisiones. Permanecen dentro de la cabina acústica. Compatibilidad de revisión pendiente de fabricante.","Todas las alturas parciales son hipótesis de visualización; solo la altura total de 3,38 m está acotada.","Las regiones del dibujo se usan como envolventes de cuerpos; la identificación funcional y la cota Z de cada pieza requieren verificación.","Pequeños taladros, tornillería y detalles interiores de las regiones no se extruyen como vacíos de fabricación.","El bastidor documentado mide 2,35 × 5,22 m. Los accesorios del detalle de abril sobresalen; el conjunto refinado ocupa aproximadamente 2,596 × 6,268 m en ejes del fabricante, pendiente de coordinación entre revisiones.","El acabado de grout HA-35 de 50 mm termina en +0,400; el hormigón termina en +0,350. La losa MAC contigua termina en +0,200.","El cero absoluto de la revisión no está definido; 286,10 m sigue siendo una hipótesis de coordinación.","Se alinea el punto inferior del conjunto del equipo, incluidos los pies ya representados, con la superficie de apoyo terminada; no se añade un espesor de calzos, placa o grout del fabricante no documentado."] | {"revision":"Detalle en planta de 2026-04-30 coordinado de forma preliminar con envolventes y alturas de 2026-08-25","status":"provisional","verticalRule":"Altura total documentada: 3,38 m. Plataforma gráfica de 0,15 m; los cuerpos extraídos de la planta reciben alturas provisionales entre 1,00 y 3,38 m, detalladas por subvolumen. No se dispone de alzado acotado de cada componente.","partCount":26,"source":{"documentId":"EQ-IMPLANTACION-20260430","title":"Plano del fabricante: implantación de equipos","sheet":"LHD2609-GD01000 · espacio modelo","date":"2026-04-30"},"heightSource":{"documentId":"EQ-CARGAS-20260825","title":"Plano del fabricante: cargas de equipos","sheet":"Espacio modelo","date":"2026-08-25"},"unconfirmedDimensions":["Todas las alturas parciales son hipótesis de visualización; solo la altura total de 3,38 m está acotada.","Las regiones del dibujo se usan como envolventes de cuerpos; la identificación funcional y la cota Z de cada pieza requieren verificación.","Pequeños taladros, tornillería y detalles interiores de las regiones no se extruyen como vacíos de fabricación."],"quantityUse":"Magnitudes de la geometría representada; no son cantidades de material, obra, compra, capacidad útil ni fabricación. En geometrías compuestas se suman superficies y volúmenes de partes y pueden existir solapes no depurados.","partsAreBOM":false} | equipment_component | {"min":[60.820401,68.378413,1.5],"max":[63.997985,74.78294,4.88]} | {"boundingBoxM":{"min":[60.820401,68.378413,1.5],"max":[63.997985,74.78294,4.88]},"extentsM":[3.177584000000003,6.404527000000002,3.38],"meshSurfaceM2":165.19823143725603,"meshVolumeM3":20.170106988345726,"closedSolid":true,"windingConsistent":true,"basis":"Submalla exacta de los triángulos del modelo IFC coordinado; separación de componentes sin transformación ni retesselación."} | ["Todas las alturas parciales son hipótesis de visualización; solo la altura total de 3,38 m está acotada.","Las regiones del dibujo se usan como envolventes de cuerpos; la identificación funcional y la cota Z de cada pieza requieren verificación.","Pequeños taladros, tornillería y detalles interiores de las regiones no se extruyen como vacíos de fabricación.","La separación gráfica no aporta cotas de fabricación ni identifica piezas internas no documentadas.","Los materiales y acabados permanecen provisionales; las fotografías públicas solo orientan la apariencia."] | {"id":"AC1001C--cad-region-028","sourcePartId":"AC1001C--cad-region-028","name":"Cuerpo de equipo · región CAD 28","role":"equipment_component","classificationStatus":"provisional","classificationBasis":"Rol del subvolumen gráfico según el activo de detalle; identidad de fabricación no confirmada.","parentEquipmentId":"AC1001C","parentEquipmentGuid":"2IJ0PLLizIvfouRXAkczXf","isAssemblyIdentityCarrier":false,"sourceFaceRange":[1776,2268],"sourceCurrentFaceIndices":[1776,1777,1778,1779,1780,1781,1782,1783,1784,1785,1786,1787,1788,1789,1790,1791,1792,1793,1794,1795,1796,1797,1798,1799,1800,1801,1802,1803,1804,1805,1806,1807,1808,1809,1810,1811,1812,1813,1814,1815,1816,1817,1818,1819,1820,1821,1822,1823,1824,1825,1826,1827,1828,1829,1830,1831,1832,1833,1834,1835,1836,1837,1838,1839,1840,1841,1842,1843,1844,1845,1846,1847,1848,1849,1850,1851,1852,1853,1854,1855,1856,1857,1858,1859,1860,1861,1862,1863,1864,1865,1866,1867,1868,1869,1870,1871,1872,1873,1874,1875,1876,1877,1878,1879,1880,1881,1882,1883,1884,1885,1886,1887,1888,1889,1890,1891,1892,1893,1894,1895,1896,1897,1898,1899,1900,1901,1902,1903,1904,1905,1906,1907,1908,1909,1910,1911,1912,1913,1914,1915,1916,1917,1918,1919,1920,1921,1922,1923,1924,1925,1926,1927,1928,1929,1930,1931,1932,1933,1934,1935,1936,1937,1938,1939,1940,1941,1942,1943,1944,1945,1946,1947,1948,1949,1950,1951,1952,1953,1954,1955,1956,1957,1958,1959,1960,1961,1962,1963,1964,1965,1966,1967,1968,1969,1970,1971,1972,1973,1974,1975,1976,1977,1978,1979,1980,1981,1982,1983,1984,1985,1986,1987,1988,1989,1990,1991,1992,1993,1994,1995,1996,1997,1998,1999,2000,2001,2002,2003,2004,2005,2006,2007,2008,2009,2010,2011,2012,2013,2014,2015,2016,2017,2018,2019,2020,2021,2022,2023,2024,2025,2026,2027,2028,2029,2030,2031,2032,2033,2034,2035,2036,2037,2038,2039,2040,2041,2042,2043,2044,2045,2046,2047,2048,2049,2050,2051,2052,2053,2054,2055,2056,2057,2058,2059,2060,2061,2062,2063,2064,2065,2066,2067,2068,2069,2070,2071,2072,2073,2074,2075,2076,2077,2078,2079,2080,2081,2082,2083,2084,2085,2086,2087,2088,2089,2090,2091,2092,2093,2094,2095,2096,2097,2098,2099,2100,2101,2102,2103,2104,2105,2106,2107,2108,2109,2110,2111,2112,2113,2114,2115,2116,2117,2118,2119,2120,2121,2122,2123,2124,2125,2126,2127,2128,2129,2130,2131,2132,2133,2134,2135,2136,2137,2138,2139,2140,2141,2142,2143,2144,2145,2146,2147,2148,2149,2150,2151,2152,2153,2154,2155,2156,2157,2158,2159,2160,2161,2162,2163,2164,2165,2166,2167,2168,2169,2170,2171,2172,2173,2174,2175,2176,2177,2178,2179,2180,2181,2182,2183,2184,2185,2186,2187,2188,2189,2190,2191,2192,2193,2194,2195,2196,2197,2198,2199,2200,2201,2202,2203,2204,2205,2206,2207,2208,2209,2210,2211,2212,2213,2214,2215,2216,2217,2218,2219,2220,2221,2222,2223,2224,2225,2226,2227,2228,2229,2230,2231,2232,2233,2234,2235,2236,2237,2238,2239,2240,2241,2242,2243,2244,2245,2246,2247,2248,2249,2250,2251,2252,2253,2254,2255,2256,2257,2258,2259,2260,2261,2262,2263,2264,2265,2266,2267],"sourceMeshSha256":"7b60c904c9d84d22fded9be34af09a09a9c198ec8e75e61902634d5e4064c761","sourceVertexIndices":[934,935,936,937,938,939,940,941,942,943,944,945,946,947,948,949,950,951,952,953,954,955,956,957,958,959,960,961,962,963,964,965,966,967,968,969,970,971,972,973,974,975,976,977,978,979,980,981,982,983,984,985,986,987,988,989,990,991,992,993,994,995,996,997,998,999,1000,1001,1002,1003,1004,1005,1006,1007,1008,1009,1010,1011,1012,1013,1014,1015,1016,1017,1018,1019,1020,1021,1022,1023,1024,1025,1026,1027,1028,1029,1030,1031,1032,1033,1034,1035,1036,1037,1038,1039,1040,1041,1042,1043,1044,1045,1046,1047,1048,1049,1050,1051,1052,1053,1054,1055,1056,1057,1058,1059,1060,1061,1062,1063,1064,1065,1066,1067,1068,1069,1070,1071,1072,1073,1074,1075,1076,1077,1078,1079,1080,1081,1082,1083,1084,1085,1086,1087,1088,1089,1090,1091,1092,1093,1094,1095,1096,1097,1098,1099,1100,1101,1102,1103,1104,1105,1106,1107,1108,1109,1110,1111,1112,1113,1114,1115,1116,1117,1118,1119,1120,1121,1122,1123,1124,1125,1126,1127,1128,1129,1130,1131,1132,1133,1134,1135,1136,1137,1138,1139,1140,1141,1142,1143,1144,1145,1146,1147,1148,1149,1150,1151,1152,1153,1154,1155,1156,1157,1158,1159,1160,1161,1162,1163,1164,1165,1166,1167,1168,1169,1170,1171,1172,1173,1174,1175,1176,1177,1178,1179,1180,1181],"separationMethod":"Partición exacta de triángulos existentes; coordenadas y orientación de caras conservadas.","quantityUse":"Magnitudes geométricas del subvolumen; no son cantidades netas de material, fabricación, suministro o capacidad."} | {"id":"AC1001C","name":"Compresor de aire AC1001C","relationship":"decomposed_component","parentShapeMeaning":"La forma del objeto que conserva el ID del equipo es únicamente su componente principal; el conjunto completo requiere sus hijos."} | {"kind":"through_parent","parentEquipmentId":"AC1001C","directAnchorageVerified":false,"note":"La relación del conjunto con cimentaciones se conserva en el objeto que mantiene el ID del equipo; no se atribuye fijación directa a cada subcomponente."} | Documento de implantación y apoyo del conjunto padre; no acredita fijación individual de este componente. | AC1001C--cad-region-028 | Cuerpo de equipo · región CAD 28 | Equipos | unknown | equipment_light_gray | {"documentId":"EQ-IMPLANTACION-20260430","title":"Plano del fabricante: implantación de equipos","sheet":"LHD2609-GD01000 · espacio modelo","date":"2026-04-30","componentSourceHandles":["717FF","71801","71803","71805","71A46","71A58","71A59","71BA6","71BA7","71DB1","71DB2","71DB4","71DB5","72EE3","72EE5","72EE6","72EEA","72EEB","72EEF","72EF0","72EF3","72EF4","72EF6","72F00","72F01","72F02","72F0D","72F0E","72F0F","72F11","73157","73158","73159","7315A","7315B","7315C","731BD","731C4","731C5","731C7","731CB","731CC","731CD","731D9","731DE","731DF","731E0","731E1","731E2","731E3","731E4","731E5","731E6","731EE","731EF","731F0","731F1","731F2","731F3","731F4","731F5","731F6","731F7","731F9","731FF","73200","73201","73202","73204","73205","73206","73207","7320B","7320D","7320E","7320F","73210","73212","7321C","7321D"]} | Submalla de triángulos existentes; no hay nueva posición ni nuevas caras. | Cotas globales del conjunto conservadas aparte; las dimensiones de esta ficha son de la submalla. | Coordinación del conjunto padre; anclaje directo individual no acreditado. | Superficie y volumen geométricos brutos; no constituyen cantidades netas de obra, material o fabricación. | Plano general y dimensiones globales de AC1001C; no se asignan esas dimensiones globales a este componente. | ["717FF","71801","71803","71805","71A46","71A58","71A59","71BA6","71BA7","71DB1","71DB2","71DB4","71DB5","72EE3","72EE5","72EE6","72EEA","72EEB","72EEF","72EF0","72EF3","72EF4","72EF6","72F00","72F01","72F02","72F0D","72F0E","72F0F","72F11","73157","73158","73159","7315A","7315B","7315C","731BD","731C4","731C5","731C7","731CB","731CC","731CD","731D9","731DE","731DF","731E0","731E1","731E2","731E3","731E4","731E5","731E6","731EE","731EF","731F0","731F1","731F2","731F3","731F4","731F5","731F6","731F7","731F9","731FF","73200","73201","73202","73204","73205","73206","73207","7320B","7320D","7320E","7320F","73210","73212","7321C","7321D"] | 1 | no | Submalla exacta; interpretación funcional y cotas parciales provisionales.
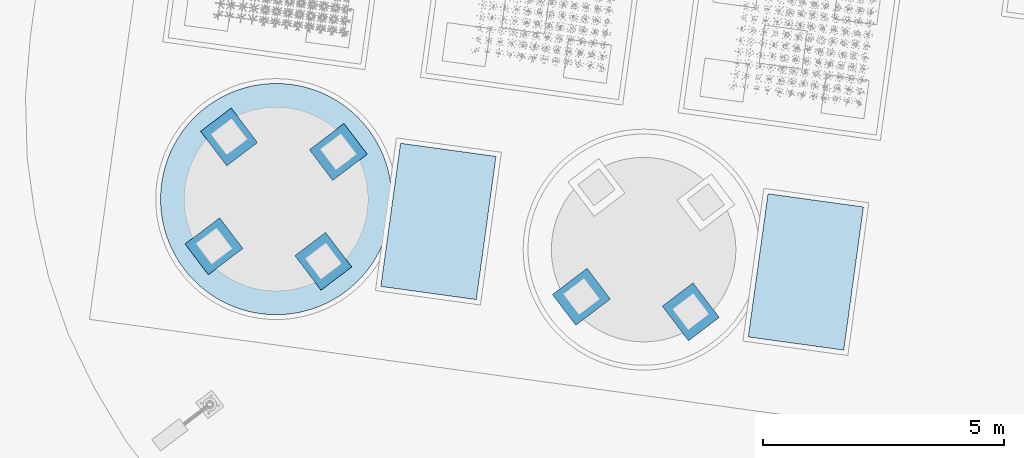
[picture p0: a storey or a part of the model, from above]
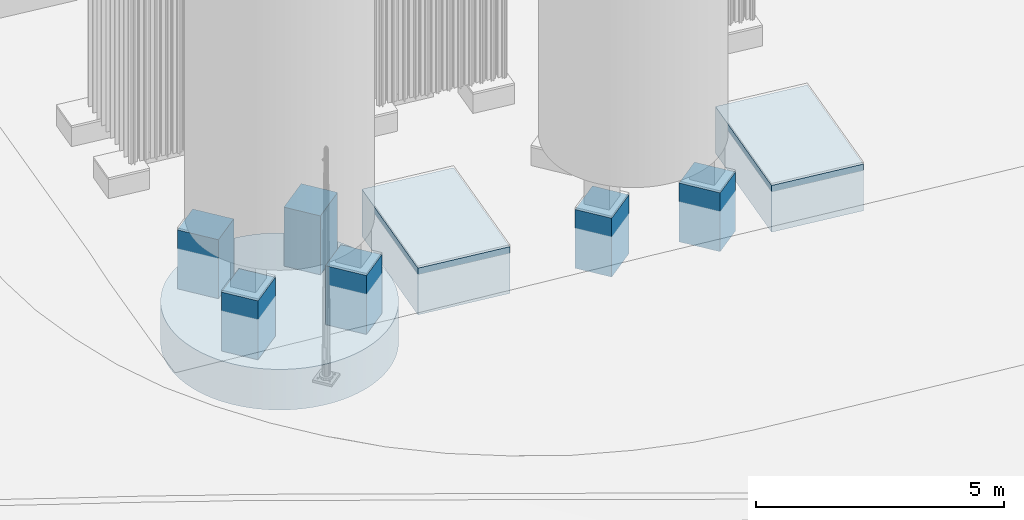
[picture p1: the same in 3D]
Properties of the parts of a building model (IFC4), part 51 of 134

# IfcBuildingElementProxy (140)
Name | Description | Document | Extensión de la malla en X (m) = ExtensionX (m) | Extensión de la malla en Y (m) = ExtensionY (m) | Extensión de la malla en Z (m) = ExtensionZ (m) | Cota inferior de visualización (m) | Cota superior de visualización (m) | SuperficieDeLaMalla (m2) | VolumenGeometrico (m3) | level | category = Categoria = Funcion | representationKind | material | dimensions | JH_InformacionBIM, source = DocumentoFuente | positioning = PosicionYEstado | issues | detailGeometry | geometryMetrics | installationSource | layerId = IdentificadorCapa | visualLayer | materialAppearance | componentSeparation | visualizationIdentity | classification | appearance | Disciplina | Material | Capa BIM = NombreCapa | Acabado de visualización = Acabado | Estado del acabado = Estado | Identificador | JH_Trazabilidad, IncidenciasPendientes | UsoDeLasMagnitudes | JH_EvidenciaDeMaterial, source | JH_DetalleGeometrico, source | VisibilidadInicial | Perfil | ColorRGB | Rugosidad | Metallicidad | Referencia | Nota | Group | parentEquipmentId = Identificador del equipo padre | parentEquipmentName = Equipo padre | parentEquipmentIfcClass | parentEquipmentDimensions | parentEquipmentPositioning | parentEquipmentIssues | parentEquipmentDetail | componentRole = Rol del componente | assemblyBBox | assemblyGeometryMetrics | manufacturerDetailsPending | component | assembly | foundationRelationship | installationSourceScope | Identificador del elemento = sourcePartId | Componente | Capa de visualización | Estado del material | Perfil visual del material | Fuente del componente | Criterio de partición | Criterio de las dimensiones | Relación con cimentaciones | Aplicabilidad de las mediciones | Referencia dimensional del conjunto | sourceHandles | partCount | partsAreBOM | status
Ámbito del expansor norte · volumen provisional | Esquema provisional solicitado para coordinación visual. No apto para construcción, fabricación, compra o medición; las magnitudes de malla no son cantidades de obra. | Plano del fabricante: implantación de equipos · referencia E7; Cimentaciones de equipos y pedestales del fabricante · revisión recibida 04/09/2026; Esquema tridimensional provisional solicitado para coordinación visual; Soportes de equipos SL1201 y SL401/402; Planta de estructuras metálicas; Plantas generales de instrumentación; Alumbrado de la caja fría |  |  |  |  |  |  |  | Coordinación visual; datum absoluto de proceso provisional | Volumen de referencia del ámbito de equipo; configuración física sin confirmar | conceptualVolume | {"name":"No especificado","source":"No se han recibido especificaciones de este elemento.","status":"unknown"} | {"documented":[{"label":"Dimensión X local del contorno CAD","value":3.590056,"unit":"m","source":"EQ-IMPLANTACION-20260430 · contorno CAD · handles 91591,91592,91593,9159A","status":"derivado"},{"label":"Dimensión Y local del contorno CAD","value":3.3,"unit":"m","source":"EQ-IMPLANTACION-20260430 · contorno CAD · handles 91591,91592,91593,9159A","status":"derivado"},{"label":"Cota relativa de la superficie de apoyo","value":0.1,"unit":"m","source":"LHD2609-JG00100-20260904 · sección 4 / 4-4 / 4a-4a · 1FE9E, 1FF16, 1FF22","status":"documentado"}],"assumed":[{"label":"Altura ilustrativa del ámbito","value":6.0,"unit":"m","source":"Altura elegida para esquema de coordinación; no procede de una cota de fabricante ni de una medición fotográfica.","status":"supuesto"}],"geometry":[{"label":"Extensión de la malla en X","value":4.006073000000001,"unit":"m","source":"Malla del esquema provisional; magnitud gráfica sin confirmación del fabricante","status":"derivado_del_esquema"},{"label":"Extensión de la malla en Y","value":3.758227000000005,"unit":"m","source":"Malla del esquema provisional; magnitud gráfica sin confirmación del fabricante","status":"derivado_del_esquema"},{"label":"Extensión de la malla en Z","value":6.0,"unit":"m","source":"Malla del esquema provisional; magnitud gráfica sin confirmación del fabricante","status":"derivado_del_esquema"},{"label":"Cota inferior de visualización","value":286.2,"unit":"m","source":"Malla del esquema provisional; magnitud gráfica sin confirmación del fabricante","status":"datum_provisional"},{"label":"Cota superior de visualización","value":292.2,"unit":"m","source":"Malla del esquema provisional; magnitud gráfica sin confirmación del fabricante","status":"datum_provisional"}],"notes":["ESQUEMA PROVISIONAL · NO APTO PARA CONSTRUCCIÓN, FABRICACIÓN, COMPRA O MEDICIÓN. Las formas y dimensiones supuestas no están verificadas por el fabricante.","Las cotas y dimensiones del apoyo o ámbito documentado no confirman las dimensiones de los elementos superiores."]} | {"documentId":"EQ-IMPLANTACION-20260430","title":"Plano del fabricante: implantación de equipos · referencia E7","sheet":"Espacio modelo; referencia E7 en el nombre del archivo","date":"2026-04-30","sourceScope":"Solo ámbito XY del plano. La altura del esquema no procede de este documento."} | {"Estado de la planta":"Derivado del CAD y del giro de implantación","Nivel relativo del apoyo (m)":0.1,"Estado del nivel relativo":"Documentado en el plano de cimentaciones","Cero absoluto de visualización (m)":286.1,"Estado del cero absoluto":"Provisional","Cota del apoyo de visualización (m)":286.20000000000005,"Desplazamiento aplicado a la malla (m)":0.10000000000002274,"Criterio":"Nivel de apoyo relativo documentado. Se adopta el cero de proceso a 286,10 m solo para visualización; la equivalencia absoluta no está confirmada. No se añade un espesor de montaje sin cota del fabricante."} | ["ESQUEMA PROVISIONAL · NO APTO PARA CONSTRUCCIÓN, FABRICACIÓN, COMPRA O MEDICIÓN. Las formas y dimensiones supuestas no están verificadas por el fabricante.","No se interpreta este ámbito como una envolvente física separada del conjunto de caja fría; faltan alzados y montaje del fabricante.","GD05001, lámina 2: +3,800 m corresponde al techo de la caja de paso del expansor; +6,050 m al soporte SL401/402; +0,100 m al apoyo inferior. No equivalen a las alturas físicas de los expansores. Relación con cada envolvente del modelo pendiente de confirmar; se conservan los volúmenes provisionales.","DQ05000 H1 contiene cuatro alzados de alumbrado y LAMP1–15. El texto chino indica poste de 2,0 m y el inglés 2,5 m: discrepancia pendiente. Los alzados sin cotas no confirman la altura total del equipo ni los niveles de plataformas."] |  | {"boundingBoxM":{"min":[54.128395,45.830887,1.2],"max":[58.134468,49.589114,7.2]},"extentsM":[4.006073,3.758227,6.0],"meshSurfaceM2":106.375055,"meshVolumeM3":71.083123,"closedSolid":true,"basis":"Esquema provisional solicitado para coordinación visual. No apto para construcción, fabricación, compra o medición; las magnitudes de malla no son cantidades de obra."} | {"documentId":"LHD2609-JG00100-20260904","title":"Cimentaciones y pedestales de equipos · revisión recibida 04/09/2026","date":"2026-09-04","sheet":"4 / 4-4 / 4a-4a","sourceHandles":["1FE9E","1FF16","1FF22"]} | equipment | {"id":"equipment","name":"Equipos"} | {"profileId":"concept_equipment","name":"Ámbito de equipo · ámbar provisional","materialName":"No especificado","physicalMaterialStatus":"unknown","physicalMaterialSource":"Pendiente de documentación del fabricante","appearanceStatus":"esquema_provisional","appearanceBasis":"Color de identificación de geometría supuesta; no representa una especificación de acabado.","note":"Apariencia gráfica de hipótesis; no confirma el material físico."} | {"status":"objeto_independiente","note":"Parte del esquema seleccionable de forma independiente; no es un despiece de fabricación."} | {"elementId":"CB-EXP-N-CONCEPT","ifcGuid":"2rEQum_sHV3wMEcZBU1Ffo","ifcClass":"IfcBuildingElementProxy","buildingId":"process_plant","buildingName":"Planta de proceso","sourceDocumentId":"EQ-IMPLANTACION-20260430","sourceRepresentationKind":"conceptualVolume"} | {"layerId":"equipment","layerName":"Equipos","role":"Volumen de referencia del ámbito de equipo; configuración física sin confirmar","basis":"Clasificación funcional del esquema, sin confirmar una configuración fabricada."} | {"profileId":"concept_equipment","name":"Ámbito de equipo · ámbar provisional","status":"esquema_provisional","basis":"Color de identificación de geometría supuesta; no representa una especificación de acabado.","physicalMaterialUnchanged":true} |  | No especificado | Equipos | Ámbito de equipo · ámbar provisional | esquema_provisional | CB-EXP-N-CONCEPT | ["ESQUEMA PROVISIONAL · NO APTO PARA CONSTRUCCIÓN, FABRICACIÓN, COMPRA O MEDICIÓN. Las formas y dimensiones supuestas no están verificadas por el fabricante.","No se interpreta este ámbito como una envolvente física separada del conjunto de caja fría; faltan alzados y montaje del fabricante.","GD05001, lámina 2: +3,800 m corresponde al techo de la caja de paso del expansor; +6,050 m al soporte SL401/402; +0,100 m al apoyo inferior. No equivalen a las alturas físicas de los expansores. Relación con cada envolvente del modelo pendiente de confirmar; se conservan los volúmenes provisionales.","DQ05000 H1 contiene cuatro alzados de alumbrado y LAMP1–15. El texto chino indica poste de 2,0 m y el inglés 2,5 m: discrepancia pendiente. Los alzados sin cotas no confirman la altura total del equipo ni los niveles de plataformas."] | Geometría de coordinación basada en planos recibidos; no sustituye el modelo de fabricación ni una medición certificada. Datum absoluto de proceso provisional. | No se han recibido especificaciones de este elemento. |  | yes | concept_equipment | [0.92,0.64,0.24] | 0.55 | 0.12 | Color de identificación de geometría supuesta; no representa una especificación de acabado. |  | BIM · Equipos; Esquemas provisionales · no para construcción | JH_InformacionBIM - foundationIds: ["found_0904_f7e6bebab60859","found_0904_ab1632a7d9dd78","found_0904_e82a8a5ec7336e","found_0904_323dc0fbe26a0b","found_0904_3aab66a70a9bd0","found_0904_33c531229e93fa"]; heightStatus: illustrative_not_documented; heightReference: {"valueM":6.0,"status":"illustrative_not_documented","sourceSupported":false,"sourceRef":"CONCEPT-COORDINATION-20260908","reason":"Altura elegida para esquema de coordinación; no procede de una cota de fabricante ni de una medición fotográfica.","sourceNote":"Altura elegida para esquema de coordinación; no procede de una cota de fabricante ni de una medición fotográfica."}; quantityEligible: no; conceptual: {"enabled":true,"userRequestedProvisional3D":true,"basis":"El ámbito XY y el apoyo se conservan del plano fuente CB-EXP-N-PLAN. Se añade una altura elegida de 6 m exclusivamente para lectura espacial. No confirma una caja independiente, carcasa, equipo interior ni interfaz de proceso.","status":"illustrative_not_documented","physicalHeightConfirmed":false,"quantityEligible":false,"notForConstruction":true,"dimensionsNotDerivedFromPhotos":true,"warning":"ESQUEMA PROVISIONAL · NO APTO PARA CONSTRUCCIÓN, FABRICACIÓN, COMPRA O MEDICIÓN. Las formas y dimensiones supuestas no están verificadas por el fabricante."}; physicalHeightConfirmed: no; derivedFromPlanId: CB-EXP-N-PLAN; supplementaryDrawingReview: {"fecha":"2026-09-09","estado":"Revisión documental; geometría conservada","criterio":"Documentación complementaria recibida el 09/09/2026. Tuberías: paquete actualizado el 07/08; fechas y revisiones por plano. La recepción no cambia la fecha de diseño. Se mantienen cargas del 25/08 y cimentaciones recibidas el 04/09 frente a las versiones anteriores incluidas.","documentos":["SOPC-PROCESS_020","SOPC-PROCESS_019","SOPC-INSTRUMENT_002","SOPC-ELECTRICAL_003"],"conclusiones":["GD05001, lámina 2: +3,800 m corresponde al techo de la caja de paso del expansor; +6,050 m al soporte SL401/402; +0,100 m al apoyo inferior. No equivalen a las alturas físicas de los expansores. Relación con cada envolvente del modelo pendiente de confirmar; se conservan los volúmenes provisionales.","DQ05000 H1 contiene cuatro alzados de alumbrado y LAMP1–15. El texto chino indica poste de 2,0 m y el inglés 2,5 m: discrepancia pendiente. Los alzados sin cotas no confirman la altura total del equipo ni los niveles de plataformas."]}; JH_Trazabilidad - Identificador del objeto: CB-EXP-N-CONCEPT; Estado de la información: Esquema provisional solicitado; Aplicabilidad a mediciones: No aplicable a mediciones, compras, fabricación o construcción.; Documento de origen: Plano del fabricante: implantación de equipos · referencia E7; Alcance de la geometría: Volumen de referencia del ámbito de equipo; configuración física sin confirmar; Base documental y supuestos: El ámbito XY y el apoyo se conservan del plano fuente CB-EXP-N-PLAN. Se añade una altura elegida de 6 m exclusivamente para lectura espacial. No confirma una caja independiente, carcasa, equipo interior ni interfaz de proceso.; Aviso: ESQUEMA PROVISIONAL · NO APTO PARA CONSTRUCCIÓN, FABRICACIÓN, COMPRA O MEDICIÓN. Las formas y dimensiones supuestas no están verificadas por el fabricante.; Altura ilustrativa (m): 6; Origen de la altura: Altura elegida para esquema de coordinación; no procede de una cota de fabricante ni de una medición fotográfica.; Revisión documental complementaria: {"fecha":"2026-09-09","estado":"Revisión documental; geometría conservada","criterio":"Documentación complementaria recibida el 09/09/2026. Tuberías: paquete actualizado el 07/08; fechas y revisiones por plano. La recepción no cambia la fecha de diseño. Se mantienen cargas del 25/08 y cimentaciones recibidas el 04/09 frente a las versiones anteriores incluidas.","documentos":["SOPC-PROCESS_020","SOPC-PROCESS_019","SOPC-INSTRUMENT_002"],"conclusiones":["GD05001, lámina 2: +3,800 m corresponde al techo de la caja de paso del expansor; +6,050 m al soporte SL401/402; +0,100 m al apoyo inferior. No equivalen a las alturas físicas de los expansores. Relación con cada envolvente del modelo pendiente de confirmar; se conservan los volúmenes provisionales."]}; JH_DimensionesDocumentadas - Cota relativa de la superficie de apoyo: 0.1 m; Dimensión X local del contorno CAD: 3.59006 m; Dimensión Y local del contorno CAD: 3.3 m; JH_EsquemaProvisional - EsEsquema: yes; AptoParaConstruccion: no; IncluirEnMediciones: no; AlturaFisicaConfirmada: no; Criterio: El ámbito XY y el apoyo se conservan del plano fuente CB-EXP-N-PLAN. Se añade una altura elegida de 6 m exclusivamente para lectura espacial. No confirma una caja independiente, carcasa, equipo interior ni interfaz de proceso.; Advertencia: Esquema provisional solicitado para coordinación visual. No apto para construcción, fabricación, compra o medición; las magnitudes de malla no son cantidades de obra.; DimensionesSupuestas: [{"label":"Altura ilustrativa del ámbito","value":6.0,"unit":"m","source":"Altura elegida para esquema de coordinación; no procede de una cota de fabricante ni de una medición fotográfica.","status":"supuesto"}]; JH_RevisionDocumental20260909 - Criterio: Documentación complementaria recibida el 09/09/2026. Tuberías: paquete actualizado el 07/08; fechas y revisiones por plano. La recepción no cambia la fecha de diseño. Se mantienen cargas del 25/08 y cimentaciones recibidas el 04/09 frente a las versiones anteriores incluidas.; Documentos: SOPC-PROCESS_020 | SOPC-PROCESS_019 | SOPC-INSTRUMENT_002; Conclusiones: GD05001, lámina 2: +3,800 m corresponde al techo de la caja de paso del expansor; +6,050 m al soporte SL401/402; +0,100 m al apoyo inferior. No equivalen a las alturas físicas de los expansores. Relación con cada envolvente del modelo pendiente de confirmar; se conservan los volúmenes provisionales.; GeometriaModificada: no
Ámbito del expansor oeste · volumen provisional | Esquema provisional solicitado para coordinación visual. No apto para construcción, fabricación, compra o medición; las magnitudes de malla no son cantidades de obra. | Plano del fabricante: implantación de equipos · referencia E7; Cimentaciones de equipos y pedestales del fabricante · revisión recibida 04/09/2026; Esquema tridimensional provisional solicitado para coordinación visual; Soportes de equipos SL1201 y SL401/402; Planta de estructuras metálicas; Plantas generales de instrumentación; Alumbrado de la caja fría |  |  |  |  |  |  |  | Coordinación visual; datum absoluto de proceso provisional | Volumen de referencia del ámbito de equipo; configuración física sin confirmar | conceptualVolume | {"name":"No especificado","source":"No se han recibido especificaciones de este elemento.","status":"unknown"} | {"documented":[{"label":"Dimensión X local del contorno CAD","value":3.3000000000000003,"unit":"m","source":"EQ-IMPLANTACION-20260430 · contorno CAD · handles 91590,91598,91599,91453","status":"derivado"},{"label":"Dimensión Y local del contorno CAD","value":3.59,"unit":"m","source":"EQ-IMPLANTACION-20260430 · contorno CAD · handles 91590,91598,91599,91453","status":"derivado"},{"label":"Cota relativa de la superficie de apoyo","value":0.1,"unit":"m","source":"LHD2609-JG00100-20260904 · sección 4 / 4-4 / 4a-4a · 1FE9E, 1FF16, 1FF22","status":"documentado"}],"assumed":[{"label":"Altura ilustrativa del ámbito","value":6.0,"unit":"m","source":"Altura elegida para esquema de coordinación; no procede de una cota de fabricante ni de una medición fotográfica.","status":"supuesto"}],"geometry":[{"label":"Extensión de la malla en X","value":3.758218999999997,"unit":"m","source":"Malla del esquema provisional; magnitud gráfica sin confirmación del fabricante","status":"derivado_del_esquema"},{"label":"Extensión de la malla en Y","value":4.006017,"unit":"m","source":"Malla del esquema provisional; magnitud gráfica sin confirmación del fabricante","status":"derivado_del_esquema"},{"label":"Extensión de la malla en Z","value":6.0,"unit":"m","source":"Malla del esquema provisional; magnitud gráfica sin confirmación del fabricante","status":"derivado_del_esquema"},{"label":"Cota inferior de visualización","value":286.2,"unit":"m","source":"Malla del esquema provisional; magnitud gráfica sin confirmación del fabricante","status":"datum_provisional"},{"label":"Cota superior de visualización","value":292.2,"unit":"m","source":"Malla del esquema provisional; magnitud gráfica sin confirmación del fabricante","status":"datum_provisional"}],"notes":["ESQUEMA PROVISIONAL · NO APTO PARA CONSTRUCCIÓN, FABRICACIÓN, COMPRA O MEDICIÓN. Las formas y dimensiones supuestas no están verificadas por el fabricante.","Las cotas y dimensiones del apoyo o ámbito documentado no confirman las dimensiones de los elementos superiores."]} | {"documentId":"EQ-IMPLANTACION-20260430","title":"Plano del fabricante: implantación de equipos · referencia E7","sheet":"Espacio modelo; referencia E7 en el nombre del archivo","date":"2026-04-30","sourceScope":"Solo ámbito XY del plano. La altura del esquema no procede de este documento."} | {"Estado de la planta":"Derivado del CAD y del giro de implantación","Nivel relativo del apoyo (m)":0.1,"Estado del nivel relativo":"Documentado en el plano de cimentaciones","Cero absoluto de visualización (m)":286.1,"Estado del cero absoluto":"Provisional","Cota del apoyo de visualización (m)":286.20000000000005,"Desplazamiento aplicado a la malla (m)":0.10000000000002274,"Criterio":"Nivel de apoyo relativo documentado. Se adopta el cero de proceso a 286,10 m solo para visualización; la equivalencia absoluta no está confirmada. No se añade un espesor de montaje sin cota del fabricante."} | ["ESQUEMA PROVISIONAL · NO APTO PARA CONSTRUCCIÓN, FABRICACIÓN, COMPRA O MEDICIÓN. Las formas y dimensiones supuestas no están verificadas por el fabricante.","No se interpreta este ámbito como una envolvente física separada del conjunto de caja fría; faltan alzados y montaje del fabricante.","GD05001, lámina 2: +3,800 m corresponde al techo de la caja de paso del expansor; +6,050 m al soporte SL401/402; +0,100 m al apoyo inferior. No equivalen a las alturas físicas de los expansores. Relación con cada envolvente del modelo pendiente de confirmar; se conservan los volúmenes provisionales.","DQ05000 H1 contiene cuatro alzados de alumbrado y LAMP1–15. El texto chino indica poste de 2,0 m y el inglés 2,5 m: discrepancia pendiente. Los alzados sin cotas no confirman la altura total del equipo ni los niveles de plataformas."] |  | {"boundingBoxM":{"min":[50.369247,42.763451,1.2],"max":[54.127466,46.769468,7.2]},"extentsM":[3.758219,4.006017,6.0],"meshSurfaceM2":106.374003,"meshVolumeM3":71.082003,"closedSolid":true,"basis":"Esquema provisional solicitado para coordinación visual. No apto para construcción, fabricación, compra o medición; las magnitudes de malla no son cantidades de obra."} | {"documentId":"LHD2609-JG00100-20260904","title":"Cimentaciones y pedestales de equipos · revisión recibida 04/09/2026","date":"2026-09-04","sheet":"4 / 4-4 / 4a-4a","sourceHandles":["1FE9E","1FF16","1FF22"]} | equipment | {"id":"equipment","name":"Equipos"} | {"profileId":"concept_equipment","name":"Ámbito de equipo · ámbar provisional","materialName":"No especificado","physicalMaterialStatus":"unknown","physicalMaterialSource":"Pendiente de documentación del fabricante","appearanceStatus":"esquema_provisional","appearanceBasis":"Color de identificación de geometría supuesta; no representa una especificación de acabado.","note":"Apariencia gráfica de hipótesis; no confirma el material físico."} | {"status":"objeto_independiente","note":"Parte del esquema seleccionable de forma independiente; no es un despiece de fabricación."} | {"elementId":"CB-EXP-W-CONCEPT","ifcGuid":"3RD9Fc64XKafBCkC0lA4n1","ifcClass":"IfcBuildingElementProxy","buildingId":"process_plant","buildingName":"Planta de proceso","sourceDocumentId":"EQ-IMPLANTACION-20260430","sourceRepresentationKind":"conceptualVolume"} | {"layerId":"equipment","layerName":"Equipos","role":"Volumen de referencia del ámbito de equipo; configuración física sin confirmar","basis":"Clasificación funcional del esquema, sin confirmar una configuración fabricada."} | {"profileId":"concept_equipment","name":"Ámbito de equipo · ámbar provisional","status":"esquema_provisional","basis":"Color de identificación de geometría supuesta; no representa una especificación de acabado.","physicalMaterialUnchanged":true} |  | No especificado | Equipos | Ámbito de equipo · ámbar provisional | esquema_provisional | CB-EXP-W-CONCEPT | ["ESQUEMA PROVISIONAL · NO APTO PARA CONSTRUCCIÓN, FABRICACIÓN, COMPRA O MEDICIÓN. Las formas y dimensiones supuestas no están verificadas por el fabricante.","No se interpreta este ámbito como una envolvente física separada del conjunto de caja fría; faltan alzados y montaje del fabricante.","GD05001, lámina 2: +3,800 m corresponde al techo de la caja de paso del expansor; +6,050 m al soporte SL401/402; +0,100 m al apoyo inferior. No equivalen a las alturas físicas de los expansores. Relación con cada envolvente del modelo pendiente de confirmar; se conservan los volúmenes provisionales.","DQ05000 H1 contiene cuatro alzados de alumbrado y LAMP1–15. El texto chino indica poste de 2,0 m y el inglés 2,5 m: discrepancia pendiente. Los alzados sin cotas no confirman la altura total del equipo ni los niveles de plataformas."] | Geometría de coordinación basada en planos recibidos; no sustituye el modelo de fabricación ni una medición certificada. Datum absoluto de proceso provisional. | No se han recibido especificaciones de este elemento. |  | yes | concept_equipment | [0.92,0.64,0.24] | 0.55 | 0.12 | Color de identificación de geometría supuesta; no representa una especificación de acabado. |  | BIM · Equipos; Esquemas provisionales · no para construcción | JH_InformacionBIM - foundationIds: ["found_0904_f7e6bebab60859","found_0904_ab1632a7d9dd78","found_0904_e82a8a5ec7336e","found_0904_323dc0fbe26a0b","found_0904_3aab66a70a9bd0","found_0904_33c531229e93fa"]; heightStatus: illustrative_not_documented; heightReference: {"valueM":6.0,"status":"illustrative_not_documented","sourceSupported":false,"sourceRef":"CONCEPT-COORDINATION-20260908","reason":"Altura elegida para esquema de coordinación; no procede de una cota de fabricante ni de una medición fotográfica.","sourceNote":"Altura elegida para esquema de coordinación; no procede de una cota de fabricante ni de una medición fotográfica."}; quantityEligible: no; conceptual: {"enabled":true,"userRequestedProvisional3D":true,"basis":"El ámbito XY y el apoyo se conservan del plano fuente CB-EXP-W-PLAN. Se añade una altura elegida de 6 m exclusivamente para lectura espacial. No confirma una caja independiente, carcasa, equipo interior ni interfaz de proceso.","status":"illustrative_not_documented","physicalHeightConfirmed":false,"quantityEligible":false,"notForConstruction":true,"dimensionsNotDerivedFromPhotos":true,"warning":"ESQUEMA PROVISIONAL · NO APTO PARA CONSTRUCCIÓN, FABRICACIÓN, COMPRA O MEDICIÓN. Las formas y dimensiones supuestas no están verificadas por el fabricante."}; physicalHeightConfirmed: no; derivedFromPlanId: CB-EXP-W-PLAN; supplementaryDrawingReview: {"fecha":"2026-09-09","estado":"Revisión documental; geometría conservada","criterio":"Documentación complementaria recibida el 09/09/2026. Tuberías: paquete actualizado el 07/08; fechas y revisiones por plano. La recepción no cambia la fecha de diseño. Se mantienen cargas del 25/08 y cimentaciones recibidas el 04/09 frente a las versiones anteriores incluidas.","documentos":["SOPC-PROCESS_020","SOPC-PROCESS_019","SOPC-INSTRUMENT_002","SOPC-ELECTRICAL_003"],"conclusiones":["GD05001, lámina 2: +3,800 m corresponde al techo de la caja de paso del expansor; +6,050 m al soporte SL401/402; +0,100 m al apoyo inferior. No equivalen a las alturas físicas de los expansores. Relación con cada envolvente del modelo pendiente de confirmar; se conservan los volúmenes provisionales.","DQ05000 H1 contiene cuatro alzados de alumbrado y LAMP1–15. El texto chino indica poste de 2,0 m y el inglés 2,5 m: discrepancia pendiente. Los alzados sin cotas no confirman la altura total del equipo ni los niveles de plataformas."]}; JH_Trazabilidad - Identificador del objeto: CB-EXP-W-CONCEPT; Estado de la información: Esquema provisional solicitado; Aplicabilidad a mediciones: No aplicable a mediciones, compras, fabricación o construcción.; Documento de origen: Plano del fabricante: implantación de equipos · referencia E7; Alcance de la geometría: Volumen de referencia del ámbito de equipo; configuración física sin confirmar; Base documental y supuestos: El ámbito XY y el apoyo se conservan del plano fuente CB-EXP-W-PLAN. Se añade una altura elegida de 6 m exclusivamente para lectura espacial. No confirma una caja independiente, carcasa, equipo interior ni interfaz de proceso.; Aviso: ESQUEMA PROVISIONAL · NO APTO PARA CONSTRUCCIÓN, FABRICACIÓN, COMPRA O MEDICIÓN. Las formas y dimensiones supuestas no están verificadas por el fabricante.; Altura ilustrativa (m): 6; Origen de la altura: Altura elegida para esquema de coordinación; no procede de una cota de fabricante ni de una medición fotográfica.; Revisión documental complementaria: {"fecha":"2026-09-09","estado":"Revisión documental; geometría conservada","criterio":"Documentación complementaria recibida el 09/09/2026. Tuberías: paquete actualizado el 07/08; fechas y revisiones por plano. La recepción no cambia la fecha de diseño. Se mantienen cargas del 25/08 y cimentaciones recibidas el 04/09 frente a las versiones anteriores incluidas.","documentos":["SOPC-PROCESS_020","SOPC-PROCESS_019","SOPC-INSTRUMENT_002"],"conclusiones":["GD05001, lámina 2: +3,800 m corresponde al techo de la caja de paso del expansor; +6,050 m al soporte SL401/402; +0,100 m al apoyo inferior. No equivalen a las alturas físicas de los expansores. Relación con cada envolvente del modelo pendiente de confirmar; se conservan los volúmenes provisionales."]}; JH_DimensionesDocumentadas - Cota relativa de la superficie de apoyo: 0.1 m; Dimensión X local del contorno CAD: 3.3 m; Dimensión Y local del contorno CAD: 3.59 m; JH_EsquemaProvisional - EsEsquema: yes; AptoParaConstruccion: no; IncluirEnMediciones: no; AlturaFisicaConfirmada: no; Criterio: El ámbito XY y el apoyo se conservan del plano fuente CB-EXP-W-PLAN. Se añade una altura elegida de 6 m exclusivamente para lectura espacial. No confirma una caja independiente, carcasa, equipo interior ni interfaz de proceso.; Advertencia: Esquema provisional solicitado para coordinación visual. No apto para construcción, fabricación, compra o medición; las magnitudes de malla no son cantidades de obra.; DimensionesSupuestas: [{"label":"Altura ilustrativa del ámbito","value":6.0,"unit":"m","source":"Altura elegida para esquema de coordinación; no procede de una cota de fabricante ni de una medición fotográfica.","status":"supuesto"}]; JH_RevisionDocumental20260909 - Criterio: Documentación complementaria recibida el 09/09/2026. Tuberías: paquete actualizado el 07/08; fechas y revisiones por plano. La recepción no cambia la fecha de diseño. Se mantienen cargas del 25/08 y cimentaciones recibidas el 04/09 frente a las versiones anteriores incluidas.; Documentos: SOPC-PROCESS_020 | SOPC-PROCESS_019 | SOPC-INSTRUMENT_002; Conclusiones: GD05001, lámina 2: +3,800 m corresponde al techo de la caja de paso del expansor; +6,050 m al soporte SL401/402; +0,100 m al apoyo inferior. No equivalen a las alturas físicas de los expansores. Relación con cada envolvente del modelo pendiente de confirmar; se conservan los volúmenes provisionales.; GeometriaModificada: no
Soporte C33 · montante provisional | Esquema provisional solicitado para coordinación visual. No apto para construcción, fabricación, compra o medición; las magnitudes de malla no son cantidades de obra. | Esquema tridimensional provisional solicitado para coordinación visual; Cimentaciones de equipos y pedestales del fabricante · revisión recibida 04/09/2026; Planta de estructuras metálicas; Plataformas de acceso |  |  |  |  |  |  |  | Coordinación visual; datum absoluto de proceso provisional | Parte de soporte C33 ilustrativo | conceptualVolume | {"name":"No especificado","source":"No se han recibido especificaciones de este elemento.","status":"unknown"} | {"documented":[{"label":"E del apoyo C33 en tabla del fabricante","value":16.0,"unit":"m","source":"LHD2609-JG00100-20260904 · tabla C33 · handle 2CD13","status":"documentado"},{"label":"N del apoyo C33 en tabla del fabricante","value":21.4,"unit":"m","source":"LHD2609-JG00100-20260904 · tabla C33 · handle 2CD14","status":"documentado"},{"label":"Cota relativa del apoyo C33","value":0.1,"unit":"m","source":"LHD2609-JG00100-20260904 · tabla C33 · handle 2CD9E","status":"documentado"}],"assumed":[{"label":"Altura ilustrativa del montante sobre placa","value":4.0,"unit":"m","source":"Altura elegida para esquema de coordinación; no procede de una cota de fabricante ni de una medición fotográfica.","status":"supuesto"},{"label":"Sección gráfica cuadrada del montante","value":0.15,"unit":"m","source":"Elección gráfica sin espesor de pared ni grado de acero definidos","status":"supuesto"},{"label":"Longitud ilustrativa del travesaño","value":2.2,"unit":"m","source":"Elección gráfica; no documentada","status":"supuesto"},{"label":"Sección gráfica cuadrada del travesaño","value":0.15,"unit":"m","source":"Elección gráfica sin espesor de pared ni grado de acero definidos","status":"supuesto"},{"label":"Sección gráfica de las cartelas","value":0.1,"unit":"m","source":"Elección gráfica sin espesor de pared ni grado de acero definidos","status":"supuesto"}],"geometry":[{"label":"Extensión de la malla en X","value":0.16903270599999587,"unit":"m","source":"Malla del esquema provisional; magnitud gráfica sin confirmación del fabricante","status":"derivado_del_esquema"},{"label":"Extensión de la malla en Y","value":0.16903270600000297,"unit":"m","source":"Malla del esquema provisional; magnitud gráfica sin confirmación del fabricante","status":"derivado_del_esquema"},{"label":"Extensión de la malla en Z","value":4.0,"unit":"m","source":"Malla del esquema provisional; magnitud gráfica sin confirmación del fabricante","status":"derivado_del_esquema"},{"label":"Cota inferior de visualización","value":286.2,"unit":"m","source":"Malla del esquema provisional; magnitud gráfica sin confirmación del fabricante","status":"datum_provisional"},{"label":"Cota superior de visualización","value":290.2,"unit":"m","source":"Malla del esquema provisional; magnitud gráfica sin confirmación del fabricante","status":"datum_provisional"}],"notes":["ESQUEMA PROVISIONAL · NO APTO PARA CONSTRUCCIÓN, FABRICACIÓN, COMPRA O MEDICIÓN. Las formas y dimensiones supuestas no están verificadas por el fabricante.","Las cotas y dimensiones del apoyo o ámbito documentado no confirman las dimensiones de los elementos superiores."]} | {"documentId":"CONCEPT-COORDINATION-20260908","title":"Esquema tridimensional provisional solicitado para coordinación visual","date":"2026-09-08","sheet":"Hipótesis de visualización; sin plano de fabricación","sourceScope":"Decisiones gráficas de modelado autorizadas; no incorpora dimensiones nuevas documentadas."} | {"anchorPlateCenterModelM":[51.2666465,49.039998,1.2],"anchorPlateTopModelM":1.2,"anchorStatus":"Posición y apoyo derivados de la placa documentada; no confirma el tipo de unión.","localTransverseAxis":[0.9906808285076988,-0.13620387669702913,0.0],"localLongitudinalAxis":[0.13620387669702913,0.9906808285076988,-0.0],"orientationStatus":"Se sigue el eje de implantación del plano como hipótesis gráfica; orientación de estructura no documentada.","visualizationAbsoluteBaseM":286.2,"absoluteDatumStatus":"Provisional"} | ["ESQUEMA PROVISIONAL · NO APTO PARA CONSTRUCCIÓN, FABRICACIÓN, COMPRA O MEDICIÓN. Las formas y dimensiones supuestas no están verificadas por el fabricante.","El soporte C33 es un único apoyo independiente. La placa found_0904_323dc0fbe26a0b (CAD 2423) pertenece a la caja fría y no se utiliza como segundo pie.","No se modelan soldaduras, tornillos, anclajes ni verificación resistente del soporte."] |  | {"boundingBoxM":{"min":[51.18213,48.955482,1.2],"max":[51.351163,49.124514,5.2]},"extentsM":[0.169033,0.169033,4.0],"meshSurfaceM2":2.445,"meshVolumeM3":0.09,"closedSolid":true,"basis":"Esquema provisional solicitado para coordinación visual. No apto para construcción, fabricación, compra o medición; las magnitudes de malla no son cantidades de obra."} | {"documentId":"LHD2609-JG00100-20260904","title":"Cimentaciones de equipos y pedestales del fabricante · revisión recibida 04/09/2026","date":"2026-09-04","sheet":"ZD1 / DZ-2","fileName":"LHD2609-JG00100_20260904.dwg","revisionCaveat":"Fecha de revisión tomada del nombre recibido; cajetines internos mantienen 02/07/2026 y algunos textos de plantilla.","sourceFileSha256":"b42eb027b7bc0b14c38d1d13514f4899b58a732aa8d0ba2ccf10fa2fc3192890"} | structure | {"id":"structure","name":"Estructura"} | {"profileId":"concept_structure","name":"Soporte C33 · ámbar provisional","materialName":"No especificado","physicalMaterialStatus":"unknown","physicalMaterialSource":"Pendiente de documentación del fabricante","appearanceStatus":"esquema_provisional","appearanceBasis":"Color de identificación de geometría supuesta; no representa una especificación de acabado.","note":"Apariencia gráfica de hipótesis; no confirma el material físico."} | {"status":"objeto_independiente","note":"Parte del esquema seleccionable de forma independiente; no es un despiece de fabricación."} | {"elementId":"C33-CONCEPT-POST","ifcGuid":"0z_OuOhOzLkRTiKIKg_qDg","ifcClass":"IfcBuildingElementProxy","buildingId":"process_plant","buildingName":"Planta de proceso","sourceDocumentId":"CONCEPT-COORDINATION-20260908","sourceRepresentationKind":"conceptualVolume"} | {"layerId":"structure","layerName":"Estructura","role":"Parte de soporte C33 ilustrativo","basis":"Clasificación funcional del esquema, sin confirmar una configuración fabricada."} | {"profileId":"concept_structure","name":"Soporte C33 · ámbar provisional","status":"esquema_provisional","basis":"Color de identificación de geometría supuesta; no representa una especificación de acabado.","physicalMaterialUnchanged":true} |  | No especificado | Estructura | Soporte C33 · ámbar provisional | esquema_provisional | C33-CONCEPT-POST | ["ESQUEMA PROVISIONAL · NO APTO PARA CONSTRUCCIÓN, FABRICACIÓN, COMPRA O MEDICIÓN. Las formas y dimensiones supuestas no están verificadas por el fabricante.", "El soporte C33 es un único apoyo independiente. La placa found_0904_323dc0fbe26a0b (CAD 2423) pertenece a la caja fría y no se utiliza como segundo pie.", "No se modelan soldaduras, tornillos, anclajes ni verificación resistente del soporte.", "GD05000 sitúa PT02 en E=16,000 m, N=21,400 m, coincidente en planta con el apoyo representado C33. GD06001 contiene dos láminas rotuladas PT01, con cotas superiores distintas. Correspondencia PT02/C33 y detalle aplicable pendientes: no sustituir el apoyo por una plataforma sin resolver esta discrepancia."] | Esquema provisional solicitado para coordinación visual. No apto para construcción, fabricación, compra o medición; las magnitudes de malla no son cantidades de obra. | No se han recibido especificaciones de este elemento. |  | yes | concept_structure | [0.87,0.56,0.18] | 0.55 | 0.12 | Color de identificación de geometría supuesta; no representa una especificación de acabado. |  | BIM · Estructura; Esquemas provisionales · no para construcción; C33 · soporte y dos tramos ilustrativos | JH_InformacionBIM - foundationIds: ["found_0904_d45da7c28766e5"]; heightStatus: illustrative_not_documented; heightReference: {"valueM":4.0,"status":"illustrative_not_documented","sourceSupported":false,"sourceRef":"CONCEPT-COORDINATION-20260908","reason":"Altura elegida para esquema de coordinación; no procede de una cota de fabricante ni de una medición fotográfica.","sourceNote":"Altura elegida para esquema de coordinación; no procede de una cota de fabricante ni de una medición fotográfica."}; quantityEligible: no; conceptual: {"enabled":true,"userRequestedProvisional3D":true,"basis":"Se documentan la posición y el apoyo C33, no su superestructura. Se propone un único montante con travesaño y dos cartelas; altura, secciones, luz, orientación y uniones son decisiones gráficas provisionales. El soporte C33 es un único apoyo independiente. La placa found_0904_323dc0fbe26a0b (CAD 2423) pertenece a la caja fría y no se utiliza como segundo pie.","status":"illustrative_not_documented","physicalHeightConfirmed":false,"quantityEligible":false,"notForConstruction":true,"dimensionsNotDerivedFromPhotos":true,"warning":"ESQUEMA PROVISIONAL · NO APTO PARA CONSTRUCCIÓN, FABRICACIÓN, COMPRA O MEDICIÓN. Las formas y dimensiones supuestas no están verificadas por el fabricante."}; physicalHeightConfirmed: no; assemblyId: C33-CONCEPT; supportPositionIds: ["C33"]; derivedFromFoundationId: found_0904_d45da7c28766e5; RevisionDocumentalComplementaria: {"fecha": "2026-09-09", "estado": "Revisión documental; geometría conservada", "criterio": "Documentación complementaria recibida el 09/09/2026. Tuberías: paquete actualizado el 07/08; fechas y revisiones por plano. La recepción no cambia la fecha de diseño. Se mantienen cargas del 25/08 y cimentaciones recibidas el 04/09 frente a las versiones anteriores incluidas.", "documentos": ["SOPC-PROCESS_019", "SOPC-PROCESS_028"], "conclusiones": ["GD05000 sitúa PT02 en E=16,000 m, N=21,400 m, coincidente en planta con el apoyo representado C33. GD06001 contiene dos láminas rotuladas PT01, con cotas superiores distintas. Correspondencia PT02/C33 y detalle aplicable pendientes: no sustituir el apoyo por una plataforma sin resolver esta discrepancia."]}; IncidenciasPendientes: ["ESQUEMA PROVISIONAL · NO APTO PARA CONSTRUCCIÓN, FABRICACIÓN, COMPRA O MEDICIÓN. Las formas y dimensiones supuestas no están verificadas por el fabricante.", "El soporte C33 es un único apoyo independiente. La placa found_0904_323dc0fbe26a0b (CAD 2423) pertenece a la caja fría y no se utiliza como segundo pie.", "No se modelan soldaduras, tornillos, anclajes ni verificación resistente del soporte.", "GD05000 sitúa PT02 en E=16,000 m, N=21,400 m, coincidente en planta con el apoyo representado C33. GD06001 contiene dos láminas rotuladas PT01, con cotas superiores distintas. Correspondencia PT02/C33 y detalle aplicable pendientes: no sustituir el apoyo por una plataforma sin resolver esta discrepancia."]; JH_Trazabilidad - Identificador del objeto: C33-CONCEPT-POST; Estado de la información: Esquema provisional solicitado; Aplicabilidad a mediciones: No aplicable a mediciones, compras, fabricación o construcción.; Documento de origen: Esquema tridimensional provisional solicitado para coordinación visual; Alcance de la geometría: Parte de soporte C33 ilustrativo; Base documental y supuestos: Se documentan la posición y el apoyo C33, no su superestructura. Se propone un único montante con travesaño y dos cartelas; altura, secciones, luz, orientación y uniones son decisiones gráficas provisionales. El soporte C33 es un único apoyo independiente. La placa found_0904_323dc0fbe26a0b (CAD 2423) pertenece a la caja fría y no se utiliza como segundo pie.; Aviso: ESQUEMA PROVISIONAL · NO APTO PARA CONSTRUCCIÓN, FABRICACIÓN, COMPRA O MEDICIÓN. Las formas y dimensiones supuestas no están verificadas por el fabricante.; Altura ilustrativa (m): 4; Origen de la altura: Altura elegida para esquema de coordinación; no procede de una cota de fabricante ni de una medición fotográfica.; RevisionDocumentalComplementaria: {"fecha": "2026-09-09", "estado": "Revisión documental; geometría conservada", "criterio": "Documentación complementaria recibida el 09/09/2026. Tuberías: paquete actualizado el 07/08; fechas y revisiones por plano. La recepción no cambia la fecha de diseño. Se mantienen cargas del 25/08 y cimentaciones recibidas el 04/09 frente a las versiones anteriores incluidas.", "documentos": ["SOPC-PROCESS_019", "SOPC-PROCESS_028"], "conclusiones": ["GD05000 sitúa PT02 en E=16,000 m, N=21,400 m, coincidente en planta con el apoyo representado C33. GD06001 contiene dos láminas rotuladas PT01, con cotas superiores distintas. Correspondencia PT02/C33 y detalle aplicable pendientes: no sustituir el apoyo por una plataforma sin resolver esta discrepancia."]}; JH_EsquemaProvisional - EsEsquema: yes; AptoParaConstruccion: no; IncluirEnMediciones: no; AlturaFisicaConfirmada: no; Criterio: Se documentan la posición y el apoyo C33, no su superestructura. Se propone un único montante con travesaño y dos cartelas; altura, secciones, luz, orientación y uniones son decisiones gráficas provisionales. El soporte C33 es un único apoyo independiente. La placa found_0904_323dc0fbe26a0b (CAD 2423) pertenece a la caja fría y no se utiliza como segundo pie.; Advertencia: Esquema provisional solicitado para coordinación visual. No apto para construcción, fabricación, compra o medición; las magnitudes de malla no son cantidades de obra.; DimensionesSupuestas: [{"label":"Altura ilustrativa del montante sobre placa","value":4.0,"unit":"m","source":"Altura elegida para esquema de coordinación; no procede de una cota de fabricante ni de una medición fotográfica.","status":"supuesto"},{"label":"Sección gráfica cuadrada del montante","value":0.15,"unit":"m","source":"Elección gráfica sin espesor de pared ni grado de acero definidos","status":"supuesto"},{"label":"Longitud ilustrativa del travesaño","value":2.2,"unit":"m","source":"Elección gráfica; no documentada","status":"supuesto"},{"label":"Sección gráfica cuadrada del travesaño","value":0.15,"unit":"m","source":"Elección gráfica sin espesor de pared ni grado de acero definidos","status":"supuesto"},{"label":"Sección gráfica de las cartelas","value":0.1,"unit":"m","source":"Elección gráfica sin espesor de pared ni grado de acero definidos","status":"supuesto"}]; JH_RevisionDocumental20260909 - Criterio: Documentación complementaria recibida el 09/09/2026. Tuberías: paquete actualizado el 07/08; fechas y revisiones por plano. La recepción no cambia la fecha de diseño. Se mantienen cargas del 25/08 y cimentaciones recibidas el 04/09 frente a las versiones anteriores incluidas.; Documentos: SOPC-PROCESS_019 | SOPC-PROCESS_028; Conclusiones: GD05000 sitúa PT02 en E=16,000 m, N=21,400 m, coincidente en planta con el apoyo representado C33. GD06001 contiene dos láminas rotuladas PT01, con cotas superiores distintas. Correspondencia PT02/C33 y detalle aplicable pendientes: no sustituir el apoyo por una plataforma sin resolver esta discrepancia.; GeometriaModificada: no; JH_DimensionesDocumentadas - E del apoyo C33 en tabla del fabricante: 16 m; N del apoyo C33 en tabla del fabricante: 21.4 m; Cota relativa del apoyo C33: 0.1 m
Soporte C33 · travesaño provisional | Esquema provisional solicitado para coordinación visual. No apto para construcción, fabricación, compra o medición; las magnitudes de malla no son cantidades de obra. | Esquema tridimensional provisional solicitado para coordinación visual; Cimentaciones de equipos y pedestales del fabricante · revisión recibida 04/09/2026; Planta de estructuras metálicas; Plataformas de acceso |  |  |  |  |  |  |  | Coordinación visual; datum absoluto de proceso provisional | Parte de soporte C33 ilustrativo | conceptualVolume | {"name":"No especificado","source":"No se han recibido especificaciones de este elemento.","status":"unknown"} | {"documented":[{"label":"E del apoyo C33 en tabla del fabricante","value":16.0,"unit":"m","source":"LHD2609-JG00100-20260904 · tabla C33 · handle 2CD13","status":"documentado"},{"label":"N del apoyo C33 en tabla del fabricante","value":21.4,"unit":"m","source":"LHD2609-JG00100-20260904 · tabla C33 · handle 2CD14","status":"documentado"},{"label":"Cota relativa del apoyo C33","value":0.1,"unit":"m","source":"LHD2609-JG00100-20260904 · tabla C33 · handle 2CD9E","status":"documentado"}],"assumed":[{"label":"Altura ilustrativa del montante sobre placa","value":4.0,"unit":"m","source":"Altura elegida para esquema de coordinación; no procede de una cota de fabricante ni de una medición fotográfica.","status":"supuesto"},{"label":"Sección gráfica cuadrada del montante","value":0.15,"unit":"m","source":"Elección gráfica sin espesor de pared ni grado de acero definidos","status":"supuesto"},{"label":"Longitud ilustrativa del travesaño","value":2.2,"unit":"m","source":"Elección gráfica; no documentada","status":"supuesto"},{"label":"Sección gráfica cuadrada del travesaño","value":0.15,"unit":"m","source":"Elección gráfica sin espesor de pared ni grado de acero definidos","status":"supuesto"},{"label":"Sección gráfica de las cartelas","value":0.1,"unit":"m","source":"Elección gráfica sin espesor de pared ni grado de acero definidos","status":"supuesto"}],"geometry":[{"label":"Extensión de la malla en X","value":2.199928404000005,"unit":"m","source":"Malla del esquema provisional; magnitud gráfica sin confirmación del fabricante","status":"derivado_del_esquema"},{"label":"Extensión de la malla en Y","value":0.44825065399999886,"unit":"m","source":"Malla del esquema provisional; magnitud gráfica sin confirmación del fabricante","status":"derivado_del_esquema"},{"label":"Extensión de la malla en Z","value":0.14999999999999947,"unit":"m","source":"Malla del esquema provisional; magnitud gráfica sin confirmación del fabricante","status":"derivado_del_esquema"},{"label":"Cota inferior de visualización","value":290.2,"unit":"m","source":"Malla del esquema provisional; magnitud gráfica sin confirmación del fabricante","status":"datum_provisional"},{"label":"Cota superior de visualización","value":290.35,"unit":"m","source":"Malla del esquema provisional; magnitud gráfica sin confirmación del fabricante","status":"datum_provisional"}],"notes":["ESQUEMA PROVISIONAL · NO APTO PARA CONSTRUCCIÓN, FABRICACIÓN, COMPRA O MEDICIÓN. Las formas y dimensiones supuestas no están verificadas por el fabricante.","Las cotas y dimensiones del apoyo o ámbito documentado no confirman las dimensiones de los elementos superiores."]} | {"documentId":"CONCEPT-COORDINATION-20260908","title":"Esquema tridimensional provisional solicitado para coordinación visual","date":"2026-09-08","sheet":"Hipótesis de visualización; sin plano de fabricación","sourceScope":"Decisiones gráficas de modelado autorizadas; no incorpora dimensiones nuevas documentadas."} | {"anchorPlateCenterModelM":[51.2666465,49.039998,1.2],"anchorPlateTopModelM":1.2,"anchorStatus":"Posición y apoyo derivados de la placa documentada; no confirma el tipo de unión.","localTransverseAxis":[0.9906808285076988,-0.13620387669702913,0.0],"localLongitudinalAxis":[0.13620387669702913,0.9906808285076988,-0.0],"orientationStatus":"Se sigue el eje de implantación del plano como hipótesis gráfica; orientación de estructura no documentada.","visualizationAbsoluteBaseM":286.2,"absoluteDatumStatus":"Provisional"} | ["ESQUEMA PROVISIONAL · NO APTO PARA CONSTRUCCIÓN, FABRICACIÓN, COMPRA O MEDICIÓN. Las formas y dimensiones supuestas no están verificadas por el fabricante.","El soporte C33 es un único apoyo independiente. La placa found_0904_323dc0fbe26a0b (CAD 2423) pertenece a la caja fría y no se utiliza como segundo pie.","No se modelan soldaduras, tornillos, anclajes ni verificación resistente del soporte."] |  | {"boundingBoxM":{"min":[50.166682,48.815873,5.2],"max":[52.366611,49.264123,5.35]},"extentsM":[2.199928,0.448251,0.15],"meshSurfaceM2":1.365,"meshVolumeM3":0.0495,"closedSolid":true,"basis":"Esquema provisional solicitado para coordinación visual. No apto para construcción, fabricación, compra o medición; las magnitudes de malla no son cantidades de obra."} | {"documentId":"LHD2609-JG00100-20260904","title":"Cimentaciones de equipos y pedestales del fabricante · revisión recibida 04/09/2026","date":"2026-09-04","sheet":"ZD1 / DZ-2","fileName":"LHD2609-JG00100_20260904.dwg","revisionCaveat":"Fecha de revisión tomada del nombre recibido; cajetines internos mantienen 02/07/2026 y algunos textos de plantilla.","sourceFileSha256":"b42eb027b7bc0b14c38d1d13514f4899b58a732aa8d0ba2ccf10fa2fc3192890"} | structure | {"id":"structure","name":"Estructura"} | {"profileId":"concept_structure","name":"Soporte C33 · ámbar provisional","materialName":"No especificado","physicalMaterialStatus":"unknown","physicalMaterialSource":"Pendiente de documentación del fabricante","appearanceStatus":"esquema_provisional","appearanceBasis":"Color de identificación de geometría supuesta; no representa una especificación de acabado.","note":"Apariencia gráfica de hipótesis; no confirma el material físico."} | {"status":"objeto_independiente","note":"Parte del esquema seleccionable de forma independiente; no es un despiece de fabricación."} | {"elementId":"C33-CONCEPT-BEAM","ifcGuid":"0wldzgDRnHjA8W5Isw7Oha","ifcClass":"IfcBuildingElementProxy","buildingId":"process_plant","buildingName":"Planta de proceso","sourceDocumentId":"CONCEPT-COORDINATION-20260908","sourceRepresentationKind":"conceptualVolume"} | {"layerId":"structure","layerName":"Estructura","role":"Parte de soporte C33 ilustrativo","basis":"Clasificación funcional del esquema, sin confirmar una configuración fabricada."} | {"profileId":"concept_structure","name":"Soporte C33 · ámbar provisional","status":"esquema_provisional","basis":"Color de identificación de geometría supuesta; no representa una especificación de acabado.","physicalMaterialUnchanged":true} |  | No especificado | Estructura | Soporte C33 · ámbar provisional | esquema_provisional | C33-CONCEPT-BEAM | ["ESQUEMA PROVISIONAL · NO APTO PARA CONSTRUCCIÓN, FABRICACIÓN, COMPRA O MEDICIÓN. Las formas y dimensiones supuestas no están verificadas por el fabricante.", "El soporte C33 es un único apoyo independiente. La placa found_0904_323dc0fbe26a0b (CAD 2423) pertenece a la caja fría y no se utiliza como segundo pie.", "No se modelan soldaduras, tornillos, anclajes ni verificación resistente del soporte.", "GD05000 sitúa PT02 en E=16,000 m, N=21,400 m, coincidente en planta con el apoyo representado C33. GD06001 contiene dos láminas rotuladas PT01, con cotas superiores distintas. Correspondencia PT02/C33 y detalle aplicable pendientes: no sustituir el apoyo por una plataforma sin resolver esta discrepancia."] | Esquema provisional solicitado para coordinación visual. No apto para construcción, fabricación, compra o medición; las magnitudes de malla no son cantidades de obra. | No se han recibido especificaciones de este elemento. |  | yes | concept_structure | [0.87,0.56,0.18] | 0.55 | 0.12 | Color de identificación de geometría supuesta; no representa una especificación de acabado. |  | BIM · Estructura; Esquemas provisionales · no para construcción; C33 · soporte y dos tramos ilustrativos | JH_InformacionBIM - foundationIds: ["found_0904_d45da7c28766e5"]; heightStatus: illustrative_not_documented; quantityEligible: no; conceptual: {"enabled":true,"userRequestedProvisional3D":true,"basis":"Se documentan la posición y el apoyo C33, no su superestructura. Se propone un único montante con travesaño y dos cartelas; altura, secciones, luz, orientación y uniones son decisiones gráficas provisionales. El soporte C33 es un único apoyo independiente. La placa found_0904_323dc0fbe26a0b (CAD 2423) pertenece a la caja fría y no se utiliza como segundo pie.","status":"illustrative_not_documented","physicalHeightConfirmed":false,"quantityEligible":false,"notForConstruction":true,"dimensionsNotDerivedFromPhotos":true,"warning":"ESQUEMA PROVISIONAL · NO APTO PARA CONSTRUCCIÓN, FABRICACIÓN, COMPRA O MEDICIÓN. Las formas y dimensiones supuestas no están verificadas por el fabricante."}; physicalHeightConfirmed: no; assemblyId: C33-CONCEPT; supportPositionIds: ["C33"]; derivedFromFoundationId: found_0904_d45da7c28766e5; RevisionDocumentalComplementaria: {"fecha": "2026-09-09", "estado": "Revisión documental; geometría conservada", "criterio": "Documentación complementaria recibida el 09/09/2026. Tuberías: paquete actualizado el 07/08; fechas y revisiones por plano. La recepción no cambia la fecha de diseño. Se mantienen cargas del 25/08 y cimentaciones recibidas el 04/09 frente a las versiones anteriores incluidas.", "documentos": ["SOPC-PROCESS_019", "SOPC-PROCESS_028"], "conclusiones": ["GD05000 sitúa PT02 en E=16,000 m, N=21,400 m, coincidente en planta con el apoyo representado C33. GD06001 contiene dos láminas rotuladas PT01, con cotas superiores distintas. Correspondencia PT02/C33 y detalle aplicable pendientes: no sustituir el apoyo por una plataforma sin resolver esta discrepancia."]}; IncidenciasPendientes: ["ESQUEMA PROVISIONAL · NO APTO PARA CONSTRUCCIÓN, FABRICACIÓN, COMPRA O MEDICIÓN. Las formas y dimensiones supuestas no están verificadas por el fabricante.", "El soporte C33 es un único apoyo independiente. La placa found_0904_323dc0fbe26a0b (CAD 2423) pertenece a la caja fría y no se utiliza como segundo pie.", "No se modelan soldaduras, tornillos, anclajes ni verificación resistente del soporte.", "GD05000 sitúa PT02 en E=16,000 m, N=21,400 m, coincidente en planta con el apoyo representado C33. GD06001 contiene dos láminas rotuladas PT01, con cotas superiores distintas. Correspondencia PT02/C33 y detalle aplicable pendientes: no sustituir el apoyo por una plataforma sin resolver esta discrepancia."]; parentElementId: C33-CONCEPT-POST; JH_Trazabilidad - Identificador del objeto: C33-CONCEPT-BEAM; Estado de la información: Esquema provisional solicitado; Aplicabilidad a mediciones: No aplicable a mediciones, compras, fabricación o construcción.; Documento de origen: Esquema tridimensional provisional solicitado para coordinación visual; Alcance de la geometría: Parte de soporte C33 ilustrativo; Base documental y supuestos: Se documentan la posición y el apoyo C33, no su superestructura. Se propone un único montante con travesaño y dos cartelas; altura, secciones, luz, orientación y uniones son decisiones gráficas provisionales. El soporte C33 es un único apoyo independiente. La placa found_0904_323dc0fbe26a0b (CAD 2423) pertenece a la caja fría y no se utiliza como segundo pie.; Aviso: ESQUEMA PROVISIONAL · NO APTO PARA CONSTRUCCIÓN, FABRICACIÓN, COMPRA O MEDICIÓN. Las formas y dimensiones supuestas no están verificadas por el fabricante.; RevisionDocumentalComplementaria: {"fecha": "2026-09-09", "estado": "Revisión documental; geometría conservada", "criterio": "Documentación complementaria recibida el 09/09/2026. Tuberías: paquete actualizado el 07/08; fechas y revisiones por plano. La recepción no cambia la fecha de diseño. Se mantienen cargas del 25/08 y cimentaciones recibidas el 04/09 frente a las versiones anteriores incluidas.", "documentos": ["SOPC-PROCESS_019", "SOPC-PROCESS_028"], "conclusiones": ["GD05000 sitúa PT02 en E=16,000 m, N=21,400 m, coincidente en planta con el apoyo representado C33. GD06001 contiene dos láminas rotuladas PT01, con cotas superiores distintas. Correspondencia PT02/C33 y detalle aplicable pendientes: no sustituir el apoyo por una plataforma sin resolver esta discrepancia."]}; JH_EsquemaProvisional - EsEsquema: yes; AptoParaConstruccion: no; IncluirEnMediciones: no; AlturaFisicaConfirmada: no; Criterio: Se documentan la posición y el apoyo C33, no su superestructura. Se propone un único montante con travesaño y dos cartelas; altura, secciones, luz, orientación y uniones son decisiones gráficas provisionales. El soporte C33 es un único apoyo independiente. La placa found_0904_323dc0fbe26a0b (CAD 2423) pertenece a la caja fría y no se utiliza como segundo pie.; Advertencia: Esquema provisional solicitado para coordinación visual. No apto para construcción, fabricación, compra o medición; las magnitudes de malla no son cantidades de obra.; DimensionesSupuestas: [{"label":"Altura ilustrativa del montante sobre placa","value":4.0,"unit":"m","source":"Altura elegida para esquema de coordinación; no procede de una cota de fabricante ni de una medición fotográfica.","status":"supuesto"},{"label":"Sección gráfica cuadrada del montante","value":0.15,"unit":"m","source":"Elección gráfica sin espesor de pared ni grado de acero definidos","status":"supuesto"},{"label":"Longitud ilustrativa del travesaño","value":2.2,"unit":"m","source":"Elección gráfica; no documentada","status":"supuesto"},{"label":"Sección gráfica cuadrada del travesaño","value":0.15,"unit":"m","source":"Elección gráfica sin espesor de pared ni grado de acero definidos","status":"supuesto"},{"label":"Sección gráfica de las cartelas","value":0.1,"unit":"m","source":"Elección gráfica sin espesor de pared ni grado de acero definidos","status":"supuesto"}]; JH_RevisionDocumental20260909 - Criterio: Documentación complementaria recibida el 09/09/2026. Tuberías: paquete actualizado el 07/08; fechas y revisiones por plano. La recepción no cambia la fecha de diseño. Se mantienen cargas del 25/08 y cimentaciones recibidas el 04/09 frente a las versiones anteriores incluidas.; Documentos: SOPC-PROCESS_019 | SOPC-PROCESS_028; Conclusiones: GD05000 sitúa PT02 en E=16,000 m, N=21,400 m, coincidente en planta con el apoyo representado C33. GD06001 contiene dos láminas rotuladas PT01, con cotas superiores distintas. Correspondencia PT02/C33 y detalle aplicable pendientes: no sustituir el apoyo por una plataforma sin resolver esta discrepancia.; GeometriaModificada: no; JH_DimensionesDocumentadas - E del apoyo C33 en tabla del fabricante: 16 m; N del apoyo C33 en tabla del fabricante: 21.4 m; Cota relativa del apoyo C33: 0.1 m
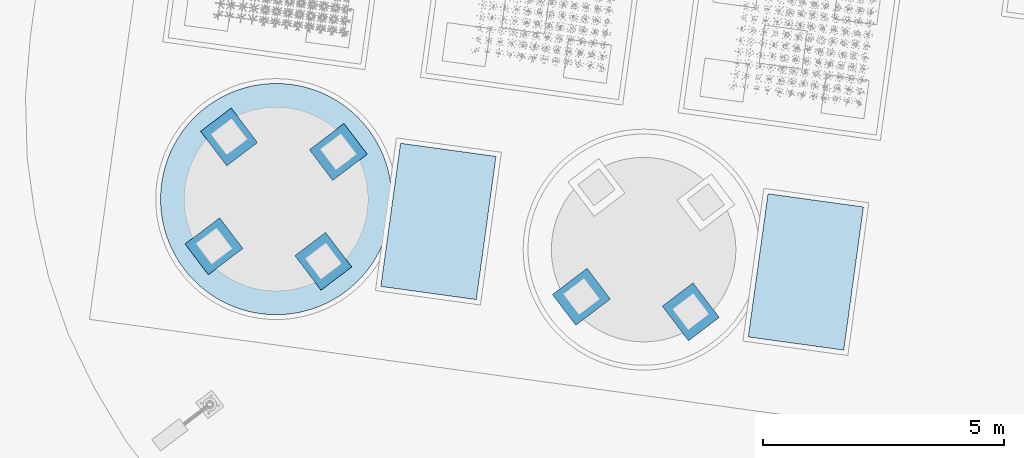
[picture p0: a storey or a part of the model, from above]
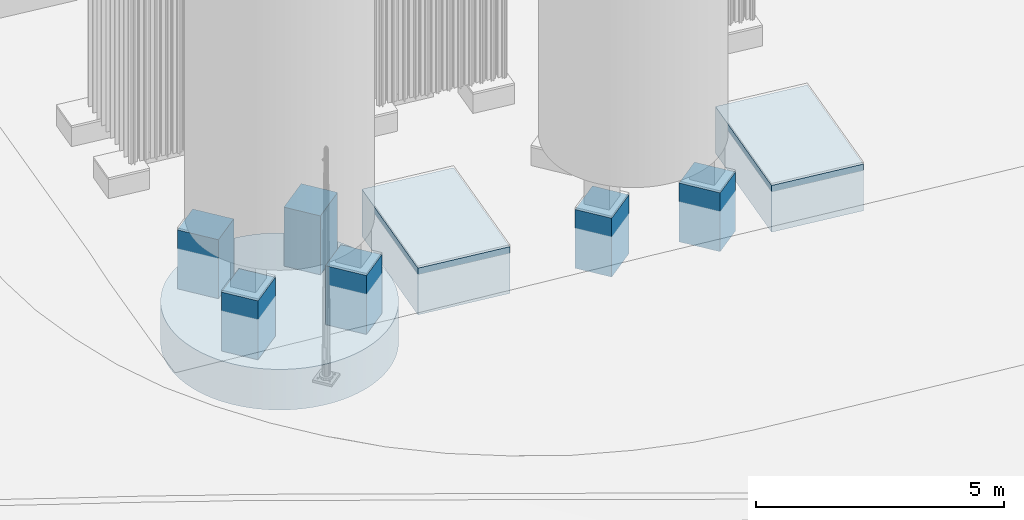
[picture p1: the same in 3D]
Properties of the parts of a building model (IFC4), part 52 of 134

# IfcBuildingElementProxy (140)
Name | Description | Document | Extensión de la malla en X (m) = ExtensionX (m) | Extensión de la malla en Y (m) = ExtensionY (m) | Extensión de la malla en Z (m) = ExtensionZ (m) | Cota inferior de visualización (m) | Cota superior de visualización (m) | SuperficieDeLaMalla (m2) | VolumenGeometrico (m3) | level | category = Categoria = Funcion | representationKind | material | dimensions | JH_InformacionBIM, source = DocumentoFuente | positioning = PosicionYEstado | issues | detailGeometry | geometryMetrics | installationSource | layerId = IdentificadorCapa | visualLayer | materialAppearance | componentSeparation | visualizationIdentity | classification | appearance | Disciplina | Material | Capa BIM = NombreCapa | Acabado de visualización = Acabado | Estado del acabado = Estado | Identificador | JH_Trazabilidad, IncidenciasPendientes | UsoDeLasMagnitudes | JH_EvidenciaDeMaterial, source | JH_DetalleGeometrico, source | VisibilidadInicial | Perfil | ColorRGB | Rugosidad | Metallicidad | Referencia | Nota | Group | parentEquipmentId = Identificador del equipo padre | parentEquipmentName = Equipo padre | parentEquipmentIfcClass | parentEquipmentDimensions | parentEquipmentPositioning | parentEquipmentIssues | parentEquipmentDetail | componentRole = Rol del componente | assemblyBBox | assemblyGeometryMetrics | manufacturerDetailsPending | component | assembly | foundationRelationship | installationSourceScope | Identificador del elemento = sourcePartId | Componente | Capa de visualización | Estado del material | Perfil visual del material | Fuente del componente | Criterio de partición | Criterio de las dimensiones | Relación con cimentaciones | Aplicabilidad de las mediciones | Referencia dimensional del conjunto | sourceHandles | partCount | partsAreBOM | status
Soporte C33 · cartela izquierda provisional | Esquema provisional solicitado para coordinación visual. No apto para construcción, fabricación, compra o medición; las magnitudes de malla no son cantidades de obra. | Esquema tridimensional provisional solicitado para coordinación visual; Cimentaciones de equipos y pedestales del fabricante · revisión recibida 04/09/2026; Planta de estructuras metálicas; Plataformas de acceso |  |  |  |  |  |  |  | Coordinación visual; datum absoluto de proceso provisional | Parte de soporte C33 ilustrativo | conceptualVolume | {"name":"No especificado","source":"No se han recibido especificaciones de este elemento.","status":"unknown"} | {"documented":[{"label":"E del apoyo C33 en tabla del fabricante","value":16.0,"unit":"m","source":"LHD2609-JG00100-20260904 · tabla C33 · handle 2CD13","status":"documentado"},{"label":"N del apoyo C33 en tabla del fabricante","value":21.4,"unit":"m","source":"LHD2609-JG00100-20260904 · tabla C33 · handle 2CD14","status":"documentado"},{"label":"Cota relativa del apoyo C33","value":0.1,"unit":"m","source":"LHD2609-JG00100-20260904 · tabla C33 · handle 2CD9E","status":"documentado"}],"assumed":[{"label":"Altura ilustrativa del montante sobre placa","value":4.0,"unit":"m","source":"Altura elegida para esquema de coordinación; no procede de una cota de fabricante ni de una medición fotográfica.","status":"supuesto"},{"label":"Sección gráfica cuadrada del montante","value":0.15,"unit":"m","source":"Elección gráfica sin espesor de pared ni grado de acero definidos","status":"supuesto"},{"label":"Longitud ilustrativa del travesaño","value":2.2,"unit":"m","source":"Elección gráfica; no documentada","status":"supuesto"},{"label":"Sección gráfica cuadrada del travesaño","value":0.15,"unit":"m","source":"Elección gráfica sin espesor de pared ni grado de acero definidos","status":"supuesto"},{"label":"Sección gráfica de las cartelas","value":0.1,"unit":"m","source":"Elección gráfica sin espesor de pared ni grado de acero definidos","status":"supuesto"}],"geometry":[{"label":"Extensión de la malla en X","value":0.8301354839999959,"unit":"m","source":"Malla del esquema provisional; magnitud gráfica sin confirmación del fabricante","status":"derivado_del_esquema"},{"label":"Extensión de la malla en Y","value":0.21132676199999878,"unit":"m","source":"Malla del esquema provisional; magnitud gráfica sin confirmación del fabricante","status":"derivado_del_esquema"},{"label":"Extensión de la malla en Z","value":0.8970445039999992,"unit":"m","source":"Malla del esquema provisional; magnitud gráfica sin confirmación del fabricante","status":"derivado_del_esquema"},{"label":"Cota inferior de visualización","value":289.366477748,"unit":"m","source":"Malla del esquema provisional; magnitud gráfica sin confirmación del fabricante","status":"datum_provisional"},{"label":"Cota superior de visualización","value":290.263522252,"unit":"m","source":"Malla del esquema provisional; magnitud gráfica sin confirmación del fabricante","status":"datum_provisional"}],"notes":["ESQUEMA PROVISIONAL · NO APTO PARA CONSTRUCCIÓN, FABRICACIÓN, COMPRA O MEDICIÓN. Las formas y dimensiones supuestas no están verificadas por el fabricante.","Las cotas y dimensiones del apoyo o ámbito documentado no confirman las dimensiones de los elementos superiores."]} | {"documentId":"CONCEPT-COORDINATION-20260908","title":"Esquema tridimensional provisional solicitado para coordinación visual","date":"2026-09-08","sheet":"Hipótesis de visualización; sin plano de fabricación","sourceScope":"Decisiones gráficas de modelado autorizadas; no incorpora dimensiones nuevas documentadas."} | {"anchorPlateCenterModelM":[51.2666465,49.039998,1.2],"anchorPlateTopModelM":1.2,"anchorStatus":"Posición y apoyo derivados de la placa documentada; no confirma el tipo de unión.","localTransverseAxis":[0.9906808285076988,-0.13620387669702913,0.0],"localLongitudinalAxis":[0.13620387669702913,0.9906808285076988,-0.0],"orientationStatus":"Se sigue el eje de implantación del plano como hipótesis gráfica; orientación de estructura no documentada.","visualizationAbsoluteBaseM":286.2,"absoluteDatumStatus":"Provisional"} | ["ESQUEMA PROVISIONAL · NO APTO PARA CONSTRUCCIÓN, FABRICACIÓN, COMPRA O MEDICIÓN. Las formas y dimensiones supuestas no están verificadas por el fabricante.","El soporte C33 es un único apoyo independiente. La placa found_0904_323dc0fbe26a0b (CAD 2423) pertenece a la caja fría y no se utiliza como segundo pie.","No se modelan soldaduras, tornillos, anclajes ni verificación resistente del soporte."] |  | {"boundingBoxM":{"min":[50.430539,48.992221,4.366478],"max":[51.260675,49.203548,5.263522]},"extentsM":[0.830135,0.211327,0.897045],"meshSurfaceM2":0.467464,"meshVolumeM3":0.011187,"closedSolid":true,"basis":"Esquema provisional solicitado para coordinación visual. No apto para construcción, fabricación, compra o medición; las magnitudes de malla no son cantidades de obra."} | {"documentId":"LHD2609-JG00100-20260904","title":"Cimentaciones de equipos y pedestales del fabricante · revisión recibida 04/09/2026","date":"2026-09-04","sheet":"ZD1 / DZ-2","fileName":"LHD2609-JG00100_20260904.dwg","revisionCaveat":"Fecha de revisión tomada del nombre recibido; cajetines internos mantienen 02/07/2026 y algunos textos de plantilla.","sourceFileSha256":"b42eb027b7bc0b14c38d1d13514f4899b58a732aa8d0ba2ccf10fa2fc3192890"} | structure | {"id":"structure","name":"Estructura"} | {"profileId":"concept_structure","name":"Soporte C33 · ámbar provisional","materialName":"No especificado","physicalMaterialStatus":"unknown","physicalMaterialSource":"Pendiente de documentación del fabricante","appearanceStatus":"esquema_provisional","appearanceBasis":"Color de identificación de geometría supuesta; no representa una especificación de acabado.","note":"Apariencia gráfica de hipótesis; no confirma el material físico."} | {"status":"objeto_independiente","note":"Parte del esquema seleccionable de forma independiente; no es un despiece de fabricación."} | {"elementId":"C33-CONCEPT-BRACE-W","ifcGuid":"1tMhkDj1rO4Ok70uLG2yCb","ifcClass":"IfcBuildingElementProxy","buildingId":"process_plant","buildingName":"Planta de proceso","sourceDocumentId":"CONCEPT-COORDINATION-20260908","sourceRepresentationKind":"conceptualVolume"} | {"layerId":"structure","layerName":"Estructura","role":"Parte de soporte C33 ilustrativo","basis":"Clasificación funcional del esquema, sin confirmar una configuración fabricada."} | {"profileId":"concept_structure","name":"Soporte C33 · ámbar provisional","status":"esquema_provisional","basis":"Color de identificación de geometría supuesta; no representa una especificación de acabado.","physicalMaterialUnchanged":true} |  | No especificado | Estructura | Soporte C33 · ámbar provisional | esquema_provisional | C33-CONCEPT-BRACE-W | ["ESQUEMA PROVISIONAL · NO APTO PARA CONSTRUCCIÓN, FABRICACIÓN, COMPRA O MEDICIÓN. Las formas y dimensiones supuestas no están verificadas por el fabricante.", "El soporte C33 es un único apoyo independiente. La placa found_0904_323dc0fbe26a0b (CAD 2423) pertenece a la caja fría y no se utiliza como segundo pie.", "No se modelan soldaduras, tornillos, anclajes ni verificación resistente del soporte.", "GD05000 sitúa PT02 en E=16,000 m, N=21,400 m, coincidente en planta con el apoyo representado C33. GD06001 contiene dos láminas rotuladas PT01, con cotas superiores distintas. Correspondencia PT02/C33 y detalle aplicable pendientes: no sustituir el apoyo por una plataforma sin resolver esta discrepancia."] | Esquema provisional solicitado para coordinación visual. No apto para construcción, fabricación, compra o medición; las magnitudes de malla no son cantidades de obra. | No se han recibido especificaciones de este elemento. |  | yes | concept_structure | [0.87,0.56,0.18] | 0.55 | 0.12 | Color de identificación de geometría supuesta; no representa una especificación de acabado. |  | BIM · Estructura; Esquemas provisionales · no para construcción; C33 · soporte y dos tramos ilustrativos | JH_InformacionBIM - foundationIds: ["found_0904_d45da7c28766e5"]; heightStatus: illustrative_not_documented; quantityEligible: no; conceptual: {"enabled":true,"userRequestedProvisional3D":true,"basis":"Se documentan la posición y el apoyo C33, no su superestructura. Se propone un único montante con travesaño y dos cartelas; altura, secciones, luz, orientación y uniones son decisiones gráficas provisionales. El soporte C33 es un único apoyo independiente. La placa found_0904_323dc0fbe26a0b (CAD 2423) pertenece a la caja fría y no se utiliza como segundo pie.","status":"illustrative_not_documented","physicalHeightConfirmed":false,"quantityEligible":false,"notForConstruction":true,"dimensionsNotDerivedFromPhotos":true,"warning":"ESQUEMA PROVISIONAL · NO APTO PARA CONSTRUCCIÓN, FABRICACIÓN, COMPRA O MEDICIÓN. Las formas y dimensiones supuestas no están verificadas por el fabricante."}; physicalHeightConfirmed: no; assemblyId: C33-CONCEPT; supportPositionIds: ["C33"]; derivedFromFoundationId: found_0904_d45da7c28766e5; RevisionDocumentalComplementaria: {"fecha": "2026-09-09", "estado": "Revisión documental; geometría conservada", "criterio": "Documentación complementaria recibida el 09/09/2026. Tuberías: paquete actualizado el 07/08; fechas y revisiones por plano. La recepción no cambia la fecha de diseño. Se mantienen cargas del 25/08 y cimentaciones recibidas el 04/09 frente a las versiones anteriores incluidas.", "documentos": ["SOPC-PROCESS_019", "SOPC-PROCESS_028"], "conclusiones": ["GD05000 sitúa PT02 en E=16,000 m, N=21,400 m, coincidente en planta con el apoyo representado C33. GD06001 contiene dos láminas rotuladas PT01, con cotas superiores distintas. Correspondencia PT02/C33 y detalle aplicable pendientes: no sustituir el apoyo por una plataforma sin resolver esta discrepancia."]}; IncidenciasPendientes: ["ESQUEMA PROVISIONAL · NO APTO PARA CONSTRUCCIÓN, FABRICACIÓN, COMPRA O MEDICIÓN. Las formas y dimensiones supuestas no están verificadas por el fabricante.", "El soporte C33 es un único apoyo independiente. La placa found_0904_323dc0fbe26a0b (CAD 2423) pertenece a la caja fría y no se utiliza como segundo pie.", "No se modelan soldaduras, tornillos, anclajes ni verificación resistente del soporte.", "GD05000 sitúa PT02 en E=16,000 m, N=21,400 m, coincidente en planta con el apoyo representado C33. GD06001 contiene dos láminas rotuladas PT01, con cotas superiores distintas. Correspondencia PT02/C33 y detalle aplicable pendientes: no sustituir el apoyo por una plataforma sin resolver esta discrepancia."]; parentElementId: C33-CONCEPT-POST; JH_Trazabilidad - Identificador del objeto: C33-CONCEPT-BRACE-W; Estado de la información: Esquema provisional solicitado; Aplicabilidad a mediciones: No aplicable a mediciones, compras, fabricación o construcción.; Documento de origen: Esquema tridimensional provisional solicitado para coordinación visual; Alcance de la geometría: Parte de soporte C33 ilustrativo; Base documental y supuestos: Se documentan la posición y el apoyo C33, no su superestructura. Se propone un único montante con travesaño y dos cartelas; altura, secciones, luz, orientación y uniones son decisiones gráficas provisionales. El soporte C33 es un único apoyo independiente. La placa found_0904_323dc0fbe26a0b (CAD 2423) pertenece a la caja fría y no se utiliza como segundo pie.; Aviso: ESQUEMA PROVISIONAL · NO APTO PARA CONSTRUCCIÓN, FABRICACIÓN, COMPRA O MEDICIÓN. Las formas y dimensiones supuestas no están verificadas por el fabricante.; RevisionDocumentalComplementaria: {"fecha": "2026-09-09", "estado": "Revisión documental; geometría conservada", "criterio": "Documentación complementaria recibida el 09/09/2026. Tuberías: paquete actualizado el 07/08; fechas y revisiones por plano. La recepción no cambia la fecha de diseño. Se mantienen cargas del 25/08 y cimentaciones recibidas el 04/09 frente a las versiones anteriores incluidas.", "documentos": ["SOPC-PROCESS_019", "SOPC-PROCESS_028"], "conclusiones": ["GD05000 sitúa PT02 en E=16,000 m, N=21,400 m, coincidente en planta con el apoyo representado C33. GD06001 contiene dos láminas rotuladas PT01, con cotas superiores distintas. Correspondencia PT02/C33 y detalle aplicable pendientes: no sustituir el apoyo por una plataforma sin resolver esta discrepancia."]}; JH_EsquemaProvisional - EsEsquema: yes; AptoParaConstruccion: no; IncluirEnMediciones: no; AlturaFisicaConfirmada: no; Criterio: Se documentan la posición y el apoyo C33, no su superestructura. Se propone un único montante con travesaño y dos cartelas; altura, secciones, luz, orientación y uniones son decisiones gráficas provisionales. El soporte C33 es un único apoyo independiente. La placa found_0904_323dc0fbe26a0b (CAD 2423) pertenece a la caja fría y no se utiliza como segundo pie.; Advertencia: Esquema provisional solicitado para coordinación visual. No apto para construcción, fabricación, compra o medición; las magnitudes de malla no son cantidades de obra.; DimensionesSupuestas: [{"label":"Altura ilustrativa del montante sobre placa","value":4.0,"unit":"m","source":"Altura elegida para esquema de coordinación; no procede de una cota de fabricante ni de una medición fotográfica.","status":"supuesto"},{"label":"Sección gráfica cuadrada del montante","value":0.15,"unit":"m","source":"Elección gráfica sin espesor de pared ni grado de acero definidos","status":"supuesto"},{"label":"Longitud ilustrativa del travesaño","value":2.2,"unit":"m","source":"Elección gráfica; no documentada","status":"supuesto"},{"label":"Sección gráfica cuadrada del travesaño","value":0.15,"unit":"m","source":"Elección gráfica sin espesor de pared ni grado de acero definidos","status":"supuesto"},{"label":"Sección gráfica de las cartelas","value":0.1,"unit":"m","source":"Elección gráfica sin espesor de pared ni grado de acero definidos","status":"supuesto"}]; JH_RevisionDocumental20260909 - Criterio: Documentación complementaria recibida el 09/09/2026. Tuberías: paquete actualizado el 07/08; fechas y revisiones por plano. La recepción no cambia la fecha de diseño. Se mantienen cargas del 25/08 y cimentaciones recibidas el 04/09 frente a las versiones anteriores incluidas.; Documentos: SOPC-PROCESS_019 | SOPC-PROCESS_028; Conclusiones: GD05000 sitúa PT02 en E=16,000 m, N=21,400 m, coincidente en planta con el apoyo representado C33. GD06001 contiene dos láminas rotuladas PT01, con cotas superiores distintas. Correspondencia PT02/C33 y detalle aplicable pendientes: no sustituir el apoyo por una plataforma sin resolver esta discrepancia.; GeometriaModificada: no; JH_DimensionesDocumentadas - E del apoyo C33 en tabla del fabricante: 16 m; N del apoyo C33 en tabla del fabricante: 21.4 m; Cota relativa del apoyo C33: 0.1 m
Soporte C33 · cartela derecha provisional | Esquema provisional solicitado para coordinación visual. No apto para construcción, fabricación, compra o medición; las magnitudes de malla no son cantidades de obra. | Esquema tridimensional provisional solicitado para coordinación visual; Cimentaciones de equipos y pedestales del fabricante · revisión recibida 04/09/2026; Planta de estructuras metálicas; Plataformas de acceso |  |  |  |  |  |  |  | Coordinación visual; datum absoluto de proceso provisional | Parte de soporte C33 ilustrativo | conceptualVolume | {"name":"No especificado","source":"No se han recibido especificaciones de este elemento.","status":"unknown"} | {"documented":[{"label":"E del apoyo C33 en tabla del fabricante","value":16.0,"unit":"m","source":"LHD2609-JG00100-20260904 · tabla C33 · handle 2CD13","status":"documentado"},{"label":"N del apoyo C33 en tabla del fabricante","value":21.4,"unit":"m","source":"LHD2609-JG00100-20260904 · tabla C33 · handle 2CD14","status":"documentado"},{"label":"Cota relativa del apoyo C33","value":0.1,"unit":"m","source":"LHD2609-JG00100-20260904 · tabla C33 · handle 2CD9E","status":"documentado"}],"assumed":[{"label":"Altura ilustrativa del montante sobre placa","value":4.0,"unit":"m","source":"Altura elegida para esquema de coordinación; no procede de una cota de fabricante ni de una medición fotográfica.","status":"supuesto"},{"label":"Sección gráfica cuadrada del montante","value":0.15,"unit":"m","source":"Elección gráfica sin espesor de pared ni grado de acero definidos","status":"supuesto"},{"label":"Longitud ilustrativa del travesaño","value":2.2,"unit":"m","source":"Elección gráfica; no documentada","status":"supuesto"},{"label":"Sección gráfica cuadrada del travesaño","value":0.15,"unit":"m","source":"Elección gráfica sin espesor de pared ni grado de acero definidos","status":"supuesto"},{"label":"Sección gráfica de las cartelas","value":0.1,"unit":"m","source":"Elección gráfica sin espesor de pared ni grado de acero definidos","status":"supuesto"}],"geometry":[{"label":"Extensión de la malla en X","value":0.8301354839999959,"unit":"m","source":"Malla del esquema provisional; magnitud gráfica sin confirmación del fabricante","status":"derivado_del_esquema"},{"label":"Extensión de la malla en Y","value":0.21132676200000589,"unit":"m","source":"Malla del esquema provisional; magnitud gráfica sin confirmación del fabricante","status":"derivado_del_esquema"},{"label":"Extensión de la malla en Z","value":0.8970445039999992,"unit":"m","source":"Malla del esquema provisional; magnitud gráfica sin confirmación del fabricante","status":"derivado_del_esquema"},{"label":"Cota inferior de visualización","value":289.366477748,"unit":"m","source":"Malla del esquema provisional; magnitud gráfica sin confirmación del fabricante","status":"datum_provisional"},{"label":"Cota superior de visualización","value":290.263522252,"unit":"m","source":"Malla del esquema provisional; magnitud gráfica sin confirmación del fabricante","status":"datum_provisional"}],"notes":["ESQUEMA PROVISIONAL · NO APTO PARA CONSTRUCCIÓN, FABRICACIÓN, COMPRA O MEDICIÓN. Las formas y dimensiones supuestas no están verificadas por el fabricante.","Las cotas y dimensiones del apoyo o ámbito documentado no confirman las dimensiones de los elementos superiores."]} | {"documentId":"CONCEPT-COORDINATION-20260908","title":"Esquema tridimensional provisional solicitado para coordinación visual","date":"2026-09-08","sheet":"Hipótesis de visualización; sin plano de fabricación","sourceScope":"Decisiones gráficas de modelado autorizadas; no incorpora dimensiones nuevas documentadas."} | {"anchorPlateCenterModelM":[51.2666465,49.039998,1.2],"anchorPlateTopModelM":1.2,"anchorStatus":"Posición y apoyo derivados de la placa documentada; no confirma el tipo de unión.","localTransverseAxis":[0.9906808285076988,-0.13620387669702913,0.0],"localLongitudinalAxis":[0.13620387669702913,0.9906808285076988,-0.0],"orientationStatus":"Se sigue el eje de implantación del plano como hipótesis gráfica; orientación de estructura no documentada.","visualizationAbsoluteBaseM":286.2,"absoluteDatumStatus":"Provisional"} | ["ESQUEMA PROVISIONAL · NO APTO PARA CONSTRUCCIÓN, FABRICACIÓN, COMPRA O MEDICIÓN. Las formas y dimensiones supuestas no están verificadas por el fabricante.","El soporte C33 es un único apoyo independiente. La placa found_0904_323dc0fbe26a0b (CAD 2423) pertenece a la caja fría y no se utiliza como segundo pie.","No se modelan soldaduras, tornillos, anclajes ni verificación resistente del soporte."] |  | {"boundingBoxM":{"min":[51.272618,48.876448,4.366478],"max":[52.102754,49.087775,5.263522]},"extentsM":[0.830135,0.211327,0.897045],"meshSurfaceM2":0.467464,"meshVolumeM3":0.011187,"closedSolid":true,"basis":"Esquema provisional solicitado para coordinación visual. No apto para construcción, fabricación, compra o medición; las magnitudes de malla no son cantidades de obra."} | {"documentId":"LHD2609-JG00100-20260904","title":"Cimentaciones de equipos y pedestales del fabricante · revisión recibida 04/09/2026","date":"2026-09-04","sheet":"ZD1 / DZ-2","fileName":"LHD2609-JG00100_20260904.dwg","revisionCaveat":"Fecha de revisión tomada del nombre recibido; cajetines internos mantienen 02/07/2026 y algunos textos de plantilla.","sourceFileSha256":"b42eb027b7bc0b14c38d1d13514f4899b58a732aa8d0ba2ccf10fa2fc3192890"} | structure | {"id":"structure","name":"Estructura"} | {"profileId":"concept_structure","name":"Soporte C33 · ámbar provisional","materialName":"No especificado","physicalMaterialStatus":"unknown","physicalMaterialSource":"Pendiente de documentación del fabricante","appearanceStatus":"esquema_provisional","appearanceBasis":"Color de identificación de geometría supuesta; no representa una especificación de acabado.","note":"Apariencia gráfica de hipótesis; no confirma el material físico."} | {"status":"objeto_independiente","note":"Parte del esquema seleccionable de forma independiente; no es un despiece de fabricación."} | {"elementId":"C33-CONCEPT-BRACE-E","ifcGuid":"36w8BMX0PTCh6i2JEvnUtd","ifcClass":"IfcBuildingElementProxy","buildingId":"process_plant","buildingName":"Planta de proceso","sourceDocumentId":"CONCEPT-COORDINATION-20260908","sourceRepresentationKind":"conceptualVolume"} | {"layerId":"structure","layerName":"Estructura","role":"Parte de soporte C33 ilustrativo","basis":"Clasificación funcional del esquema, sin confirmar una configuración fabricada."} | {"profileId":"concept_structure","name":"Soporte C33 · ámbar provisional","status":"esquema_provisional","basis":"Color de identificación de geometría supuesta; no representa una especificación de acabado.","physicalMaterialUnchanged":true} |  | No especificado | Estructura | Soporte C33 · ámbar provisional | esquema_provisional | C33-CONCEPT-BRACE-E | ["ESQUEMA PROVISIONAL · NO APTO PARA CONSTRUCCIÓN, FABRICACIÓN, COMPRA O MEDICIÓN. Las formas y dimensiones supuestas no están verificadas por el fabricante.", "El soporte C33 es un único apoyo independiente. La placa found_0904_323dc0fbe26a0b (CAD 2423) pertenece a la caja fría y no se utiliza como segundo pie.", "No se modelan soldaduras, tornillos, anclajes ni verificación resistente del soporte.", "GD05000 sitúa PT02 en E=16,000 m, N=21,400 m, coincidente en planta con el apoyo representado C33. GD06001 contiene dos láminas rotuladas PT01, con cotas superiores distintas. Correspondencia PT02/C33 y detalle aplicable pendientes: no sustituir el apoyo por una plataforma sin resolver esta discrepancia."] | Esquema provisional solicitado para coordinación visual. No apto para construcción, fabricación, compra o medición; las magnitudes de malla no son cantidades de obra. | No se han recibido especificaciones de este elemento. |  | yes | concept_structure | [0.87,0.56,0.18] | 0.55 | 0.12 | Color de identificación de geometría supuesta; no representa una especificación de acabado. |  | BIM · Estructura; Esquemas provisionales · no para construcción; C33 · soporte y dos tramos ilustrativos | JH_InformacionBIM - foundationIds: ["found_0904_d45da7c28766e5"]; heightStatus: illustrative_not_documented; quantityEligible: no; conceptual: {"enabled":true,"userRequestedProvisional3D":true,"basis":"Se documentan la posición y el apoyo C33, no su superestructura. Se propone un único montante con travesaño y dos cartelas; altura, secciones, luz, orientación y uniones son decisiones gráficas provisionales. El soporte C33 es un único apoyo independiente. La placa found_0904_323dc0fbe26a0b (CAD 2423) pertenece a la caja fría y no se utiliza como segundo pie.","status":"illustrative_not_documented","physicalHeightConfirmed":false,"quantityEligible":false,"notForConstruction":true,"dimensionsNotDerivedFromPhotos":true,"warning":"ESQUEMA PROVISIONAL · NO APTO PARA CONSTRUCCIÓN, FABRICACIÓN, COMPRA O MEDICIÓN. Las formas y dimensiones supuestas no están verificadas por el fabricante."}; physicalHeightConfirmed: no; assemblyId: C33-CONCEPT; supportPositionIds: ["C33"]; derivedFromFoundationId: found_0904_d45da7c28766e5; RevisionDocumentalComplementaria: {"fecha": "2026-09-09", "estado": "Revisión documental; geometría conservada", "criterio": "Documentación complementaria recibida el 09/09/2026. Tuberías: paquete actualizado el 07/08; fechas y revisiones por plano. La recepción no cambia la fecha de diseño. Se mantienen cargas del 25/08 y cimentaciones recibidas el 04/09 frente a las versiones anteriores incluidas.", "documentos": ["SOPC-PROCESS_019", "SOPC-PROCESS_028"], "conclusiones": ["GD05000 sitúa PT02 en E=16,000 m, N=21,400 m, coincidente en planta con el apoyo representado C33. GD06001 contiene dos láminas rotuladas PT01, con cotas superiores distintas. Correspondencia PT02/C33 y detalle aplicable pendientes: no sustituir el apoyo por una plataforma sin resolver esta discrepancia."]}; IncidenciasPendientes: ["ESQUEMA PROVISIONAL · NO APTO PARA CONSTRUCCIÓN, FABRICACIÓN, COMPRA O MEDICIÓN. Las formas y dimensiones supuestas no están verificadas por el fabricante.", "El soporte C33 es un único apoyo independiente. La placa found_0904_323dc0fbe26a0b (CAD 2423) pertenece a la caja fría y no se utiliza como segundo pie.", "No se modelan soldaduras, tornillos, anclajes ni verificación resistente del soporte.", "GD05000 sitúa PT02 en E=16,000 m, N=21,400 m, coincidente en planta con el apoyo representado C33. GD06001 contiene dos láminas rotuladas PT01, con cotas superiores distintas. Correspondencia PT02/C33 y detalle aplicable pendientes: no sustituir el apoyo por una plataforma sin resolver esta discrepancia."]; parentElementId: C33-CONCEPT-POST; JH_Trazabilidad - Identificador del objeto: C33-CONCEPT-BRACE-E; Estado de la información: Esquema provisional solicitado; Aplicabilidad a mediciones: No aplicable a mediciones, compras, fabricación o construcción.; Documento de origen: Esquema tridimensional provisional solicitado para coordinación visual; Alcance de la geometría: Parte de soporte C33 ilustrativo; Base documental y supuestos: Se documentan la posición y el apoyo C33, no su superestructura. Se propone un único montante con travesaño y dos cartelas; altura, secciones, luz, orientación y uniones son decisiones gráficas provisionales. El soporte C33 es un único apoyo independiente. La placa found_0904_323dc0fbe26a0b (CAD 2423) pertenece a la caja fría y no se utiliza como segundo pie.; Aviso: ESQUEMA PROVISIONAL · NO APTO PARA CONSTRUCCIÓN, FABRICACIÓN, COMPRA O MEDICIÓN. Las formas y dimensiones supuestas no están verificadas por el fabricante.; RevisionDocumentalComplementaria: {"fecha": "2026-09-09", "estado": "Revisión documental; geometría conservada", "criterio": "Documentación complementaria recibida el 09/09/2026. Tuberías: paquete actualizado el 07/08; fechas y revisiones por plano. La recepción no cambia la fecha de diseño. Se mantienen cargas del 25/08 y cimentaciones recibidas el 04/09 frente a las versiones anteriores incluidas.", "documentos": ["SOPC-PROCESS_019", "SOPC-PROCESS_028"], "conclusiones": ["GD05000 sitúa PT02 en E=16,000 m, N=21,400 m, coincidente en planta con el apoyo representado C33. GD06001 contiene dos láminas rotuladas PT01, con cotas superiores distintas. Correspondencia PT02/C33 y detalle aplicable pendientes: no sustituir el apoyo por una plataforma sin resolver esta discrepancia."]}; JH_EsquemaProvisional - EsEsquema: yes; AptoParaConstruccion: no; IncluirEnMediciones: no; AlturaFisicaConfirmada: no; Criterio: Se documentan la posición y el apoyo C33, no su superestructura. Se propone un único montante con travesaño y dos cartelas; altura, secciones, luz, orientación y uniones son decisiones gráficas provisionales. El soporte C33 es un único apoyo independiente. La placa found_0904_323dc0fbe26a0b (CAD 2423) pertenece a la caja fría y no se utiliza como segundo pie.; Advertencia: Esquema provisional solicitado para coordinación visual. No apto para construcción, fabricación, compra o medición; las magnitudes de malla no son cantidades de obra.; DimensionesSupuestas: [{"label":"Altura ilustrativa del montante sobre placa","value":4.0,"unit":"m","source":"Altura elegida para esquema de coordinación; no procede de una cota de fabricante ni de una medición fotográfica.","status":"supuesto"},{"label":"Sección gráfica cuadrada del montante","value":0.15,"unit":"m","source":"Elección gráfica sin espesor de pared ni grado de acero definidos","status":"supuesto"},{"label":"Longitud ilustrativa del travesaño","value":2.2,"unit":"m","source":"Elección gráfica; no documentada","status":"supuesto"},{"label":"Sección gráfica cuadrada del travesaño","value":0.15,"unit":"m","source":"Elección gráfica sin espesor de pared ni grado de acero definidos","status":"supuesto"},{"label":"Sección gráfica de las cartelas","value":0.1,"unit":"m","source":"Elección gráfica sin espesor de pared ni grado de acero definidos","status":"supuesto"}]; JH_RevisionDocumental20260909 - Criterio: Documentación complementaria recibida el 09/09/2026. Tuberías: paquete actualizado el 07/08; fechas y revisiones por plano. La recepción no cambia la fecha de diseño. Se mantienen cargas del 25/08 y cimentaciones recibidas el 04/09 frente a las versiones anteriores incluidas.; Documentos: SOPC-PROCESS_019 | SOPC-PROCESS_028; Conclusiones: GD05000 sitúa PT02 en E=16,000 m, N=21,400 m, coincidente en planta con el apoyo representado C33. GD06001 contiene dos láminas rotuladas PT01, con cotas superiores distintas. Correspondencia PT02/C33 y detalle aplicable pendientes: no sustituir el apoyo por una plataforma sin resolver esta discrepancia.; GeometriaModificada: no; JH_DimensionesDocumentadas - E del apoyo C33 en tabla del fabricante: 16 m; N del apoyo C33 en tabla del fabricante: 21.4 m; Cota relativa del apoyo C33: 0.1 m
C33 · tramo de tubería 01 provisional sin conexión | Esquema provisional solicitado para coordinación visual. No apto para construcción, fabricación, compra o medición; las magnitudes de malla no son cantidades de obra. | Esquema tridimensional provisional solicitado para coordinación visual; Cimentaciones de equipos y pedestales del fabricante · revisión recibida 04/09/2026; Planta de estructuras metálicas; Plataformas de acceso |  |  |  |  |  |  |  | Coordinación visual; datum absoluto de proceso provisional | Tramo ilustrativo de tubería; servicio y ruta sin definir | conceptualVolume | {"name":"No especificado","source":"No se han recibido especificaciones de este elemento.","status":"unknown"} | {"documented":[],"assumed":[{"label":"Longitud ilustrativa del tramo","value":3.0,"unit":"m","source":"Elección gráfica, sin trazado documentado","status":"supuesto"},{"label":"Diámetro exterior ilustrativo","value":0.1,"unit":"m","source":"Elección gráfica; sin DN, espesor, material ni fluido confirmados","status":"supuesto"},{"label":"Separación entre ejes de los dos tramos","value":0.65,"unit":"m","source":"Elección gráfica","status":"supuesto"}],"geometry":[{"label":"Extensión de la malla en X","value":0.5076797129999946,"unit":"m","source":"Malla del esquema provisional; magnitud gráfica sin confirmación del fabricante","status":"derivado_del_esquema"},{"label":"Extensión de la malla en Y","value":2.985662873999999,"unit":"m","source":"Malla del esquema provisional; magnitud gráfica sin confirmación del fabricante","status":"derivado_del_esquema"},{"label":"Extensión de la malla en Z","value":0.10000000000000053,"unit":"m","source":"Malla del esquema provisional; magnitud gráfica sin confirmación del fabricante","status":"derivado_del_esquema"},{"label":"Cota inferior de visualización","value":290.35,"unit":"m","source":"Malla del esquema provisional; magnitud gráfica sin confirmación del fabricante","status":"datum_provisional"},{"label":"Cota superior de visualización","value":290.45,"unit":"m","source":"Malla del esquema provisional; magnitud gráfica sin confirmación del fabricante","status":"datum_provisional"}],"notes":["ESQUEMA PROVISIONAL · NO APTO PARA CONSTRUCCIÓN, FABRICACIÓN, COMPRA O MEDICIÓN. Las formas y dimensiones supuestas no están verificadas por el fabricante.","Las cotas y dimensiones del apoyo o ámbito documentado no confirman las dimensiones de los elementos superiores."]} | {"documentId":"CONCEPT-COORDINATION-20260908","title":"Esquema tridimensional provisional solicitado para coordinación visual","date":"2026-09-08","sheet":"Hipótesis de visualización; sin plano de fabricación","sourceScope":"Decisiones gráficas de modelado autorizadas; no incorpora dimensiones nuevas documentadas."} | {"segmentCenterModelM":[50.944675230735,49.084264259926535,5.4],"segmentAxis":[0.13620387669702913,0.9906808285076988,-0.0],"beamTopModelM":5.3500000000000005,"pipeBottomModelM":5.3500000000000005,"status":"Apoyo por contacto gráfico; sin detalle de abrazadera o zapata"} | ["ESQUEMA PROVISIONAL · NO APTO PARA CONSTRUCCIÓN, FABRICACIÓN, COMPRA O MEDICIÓN. Las formas y dimensiones supuestas no están verificadas por el fabricante.","No conectar a equipos ni utilizar como ruta de instalación. Las líneas no tienen identificación de fluido, presión, temperatura ni clase de tubería."] |  | {"boundingBoxM":{"min":[50.690835,47.591433,5.35],"max":[51.198515,50.577096,5.45]},"extentsM":[0.50768,2.985663,0.1],"meshSurfaceM2":0.955318,"meshVolumeM3":0.023294,"closedSolid":true,"basis":"Esquema provisional solicitado para coordinación visual. No apto para construcción, fabricación, compra o medición; las magnitudes de malla no son cantidades de obra."} | {"documentId":"LHD2609-JG00100-20260904","title":"Cimentaciones de equipos y pedestales del fabricante · revisión recibida 04/09/2026","date":"2026-09-04","sheet":"ZD1 / DZ-2","fileName":"LHD2609-JG00100_20260904.dwg","revisionCaveat":"Fecha de revisión tomada del nombre recibido; cajetines internos mantienen 02/07/2026 y algunos textos de plantilla.","sourceFileSha256":"b42eb027b7bc0b14c38d1d13514f4899b58a732aa8d0ba2ccf10fa2fc3192890"} | utilities | {"id":"utilities","name":"Servicios auxiliares"} | {"profileId":"concept_pipe","name":"Tramos de tubería · azul provisional","materialName":"No especificado","physicalMaterialStatus":"unknown","physicalMaterialSource":"Pendiente de documentación del fabricante","appearanceStatus":"esquema_provisional","appearanceBasis":"Color de identificación de geometría supuesta; no representa una especificación de acabado.","note":"Apariencia gráfica de hipótesis; no confirma el material físico."} | {"status":"objeto_independiente","note":"Parte del esquema seleccionable de forma independiente; no es un despiece de fabricación."} | {"elementId":"C33-CONCEPT-PIPE-01","ifcGuid":"26kVLTunDOYe3Hj3z5nxFR","ifcClass":"IfcBuildingElementProxy","buildingId":"process_plant","buildingName":"Planta de proceso","sourceDocumentId":"CONCEPT-COORDINATION-20260908","sourceRepresentationKind":"conceptualVolume"} | {"layerId":"utilities","layerName":"Servicios auxiliares","role":"Tramo ilustrativo de tubería; servicio y ruta sin definir","basis":"Clasificación funcional del esquema, sin confirmar una configuración fabricada."} | {"profileId":"concept_pipe","name":"Tramos de tubería · azul provisional","status":"esquema_provisional","basis":"Color de identificación de geometría supuesta; no representa una especificación de acabado.","physicalMaterialUnchanged":true} |  | No especificado | Servicios auxiliares | Tramos de tubería · azul provisional | esquema_provisional | C33-CONCEPT-PIPE-01 | ["ESQUEMA PROVISIONAL · NO APTO PARA CONSTRUCCIÓN, FABRICACIÓN, COMPRA O MEDICIÓN. Las formas y dimensiones supuestas no están verificadas por el fabricante.", "No conectar a equipos ni utilizar como ruta de instalación. Las líneas no tienen identificación de fluido, presión, temperatura ni clase de tubería.", "GD05000 sitúa PT02 en E=16,000 m, N=21,400 m, coincidente en planta con el apoyo representado C33. GD06001 contiene dos láminas rotuladas PT01, con cotas superiores distintas. Correspondencia PT02/C33 y detalle aplicable pendientes: no sustituir el apoyo por una plataforma sin resolver esta discrepancia."] | Esquema provisional solicitado para coordinación visual. No apto para construcción, fabricación, compra o medición; las magnitudes de malla no son cantidades de obra. | No se han recibido especificaciones de este elemento. |  | yes | concept_pipe | [0.28,0.63,0.78] | 0.55 | 0.12 | Color de identificación de geometría supuesta; no representa una especificación de acabado. |  | BIM · Servicios auxiliares; Esquemas provisionales · no para construcción; C33 · soporte y dos tramos ilustrativos | JH_InformacionBIM - foundationIds: ["found_0904_d45da7c28766e5"]; heightStatus: illustrative_not_documented; quantityEligible: no; conceptual: {"enabled":true,"userRequestedProvisional3D":true,"basis":"Dos tramos cortos sin conexiones ilustran el uso posible de un soporte de tuberías. No son rutas de proceso ni confirman el número de líneas, su servicio, diámetro o cota real.","status":"illustrative_not_documented","physicalHeightConfirmed":false,"quantityEligible":false,"notForConstruction":true,"dimensionsNotDerivedFromPhotos":true,"warning":"ESQUEMA PROVISIONAL · NO APTO PARA CONSTRUCCIÓN, FABRICACIÓN, COMPRA O MEDICIÓN. Las formas y dimensiones supuestas no están verificadas por el fabricante."}; physicalHeightConfirmed: no; assemblyId: C33-CONCEPT; derivedFromFoundationId: found_0904_d45da7c28766e5; RevisionDocumentalComplementaria: {"fecha": "2026-09-09", "estado": "Revisión documental; geometría conservada", "criterio": "Documentación complementaria recibida el 09/09/2026. Tuberías: paquete actualizado el 07/08; fechas y revisiones por plano. La recepción no cambia la fecha de diseño. Se mantienen cargas del 25/08 y cimentaciones recibidas el 04/09 frente a las versiones anteriores incluidas.", "documentos": ["SOPC-PROCESS_019", "SOPC-PROCESS_028"], "conclusiones": ["GD05000 sitúa PT02 en E=16,000 m, N=21,400 m, coincidente en planta con el apoyo representado C33. GD06001 contiene dos láminas rotuladas PT01, con cotas superiores distintas. Correspondencia PT02/C33 y detalle aplicable pendientes: no sustituir el apoyo por una plataforma sin resolver esta discrepancia."]}; IncidenciasPendientes: ["ESQUEMA PROVISIONAL · NO APTO PARA CONSTRUCCIÓN, FABRICACIÓN, COMPRA O MEDICIÓN. Las formas y dimensiones supuestas no están verificadas por el fabricante.", "No conectar a equipos ni utilizar como ruta de instalación. Las líneas no tienen identificación de fluido, presión, temperatura ni clase de tubería.", "GD05000 sitúa PT02 en E=16,000 m, N=21,400 m, coincidente en planta con el apoyo representado C33. GD06001 contiene dos láminas rotuladas PT01, con cotas superiores distintas. Correspondencia PT02/C33 y detalle aplicable pendientes: no sustituir el apoyo por una plataforma sin resolver esta discrepancia."]; parentElementId: C33-CONCEPT-BEAM; connections: {"connected":false,"networkId":null,"service":"Desconocido","basis":"Tramo aislado de demostración; sin puertos ni conexiones de proceso definidos"}; JH_Trazabilidad - Identificador del objeto: C33-CONCEPT-PIPE-01; Estado de la información: Esquema provisional solicitado; Aplicabilidad a mediciones: No aplicable a mediciones, compras, fabricación o construcción.; Documento de origen: Esquema tridimensional provisional solicitado para coordinación visual; Alcance de la geometría: Tramo ilustrativo de tubería; servicio y ruta sin definir; Base documental y supuestos: Dos tramos cortos sin conexiones ilustran el uso posible de un soporte de tuberías. No son rutas de proceso ni confirman el número de líneas, su servicio, diámetro o cota real.; Aviso: ESQUEMA PROVISIONAL · NO APTO PARA CONSTRUCCIÓN, FABRICACIÓN, COMPRA O MEDICIÓN. Las formas y dimensiones supuestas no están verificadas por el fabricante.; RevisionDocumentalComplementaria: {"fecha": "2026-09-09", "estado": "Revisión documental; geometría conservada", "criterio": "Documentación complementaria recibida el 09/09/2026. Tuberías: paquete actualizado el 07/08; fechas y revisiones por plano. La recepción no cambia la fecha de diseño. Se mantienen cargas del 25/08 y cimentaciones recibidas el 04/09 frente a las versiones anteriores incluidas.", "documentos": ["SOPC-PROCESS_019", "SOPC-PROCESS_028"], "conclusiones": ["GD05000 sitúa PT02 en E=16,000 m, N=21,400 m, coincidente en planta con el apoyo representado C33. GD06001 contiene dos láminas rotuladas PT01, con cotas superiores distintas. Correspondencia PT02/C33 y detalle aplicable pendientes: no sustituir el apoyo por una plataforma sin resolver esta discrepancia."]}; JH_EsquemaProvisional - EsEsquema: yes; AptoParaConstruccion: no; IncluirEnMediciones: no; AlturaFisicaConfirmada: no; Criterio: Dos tramos cortos sin conexiones ilustran el uso posible de un soporte de tuberías. No son rutas de proceso ni confirman el número de líneas, su servicio, diámetro o cota real.; Advertencia: Esquema provisional solicitado para coordinación visual. No apto para construcción, fabricación, compra o medición; las magnitudes de malla no son cantidades de obra.; DimensionesSupuestas: [{"label":"Longitud ilustrativa del tramo","value":3.0,"unit":"m","source":"Elección gráfica, sin trazado documentado","status":"supuesto"},{"label":"Diámetro exterior ilustrativo","value":0.1,"unit":"m","source":"Elección gráfica; sin DN, espesor, material ni fluido confirmados","status":"supuesto"},{"label":"Separación entre ejes de los dos tramos","value":0.65,"unit":"m","source":"Elección gráfica","status":"supuesto"}]; JH_RevisionDocumental20260909 - Criterio: Documentación complementaria recibida el 09/09/2026. Tuberías: paquete actualizado el 07/08; fechas y revisiones por plano. La recepción no cambia la fecha de diseño. Se mantienen cargas del 25/08 y cimentaciones recibidas el 04/09 frente a las versiones anteriores incluidas.; Documentos: SOPC-PROCESS_019 | SOPC-PROCESS_028; Conclusiones: GD05000 sitúa PT02 en E=16,000 m, N=21,400 m, coincidente en planta con el apoyo representado C33. GD06001 contiene dos láminas rotuladas PT01, con cotas superiores distintas. Correspondencia PT02/C33 y detalle aplicable pendientes: no sustituir el apoyo por una plataforma sin resolver esta discrepancia.; GeometriaModificada: no
C33 · tramo de tubería 02 provisional sin conexión | Esquema provisional solicitado para coordinación visual. No apto para construcción, fabricación, compra o medición; las magnitudes de malla no son cantidades de obra. | Esquema tridimensional provisional solicitado para coordinación visual; Cimentaciones de equipos y pedestales del fabricante · revisión recibida 04/09/2026; Planta de estructuras metálicas; Plataformas de acceso |  |  |  |  |  |  |  | Coordinación visual; datum absoluto de proceso provisional | Tramo ilustrativo de tubería; servicio y ruta sin definir | conceptualVolume | {"name":"No especificado","source":"No se han recibido especificaciones de este elemento.","status":"unknown"} | {"documented":[],"assumed":[{"label":"Longitud ilustrativa del tramo","value":3.0,"unit":"m","source":"Elección gráfica, sin trazado documentado","status":"supuesto"},{"label":"Diámetro exterior ilustrativo","value":0.1,"unit":"m","source":"Elección gráfica; sin DN, espesor, material ni fluido confirmados","status":"supuesto"},{"label":"Separación entre ejes de los dos tramos","value":0.65,"unit":"m","source":"Elección gráfica","status":"supuesto"}],"geometry":[{"label":"Extensión de la malla en X","value":0.5076797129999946,"unit":"m","source":"Malla del esquema provisional; magnitud gráfica sin confirmación del fabricante","status":"derivado_del_esquema"},{"label":"Extensión de la malla en Y","value":2.985662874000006,"unit":"m","source":"Malla del esquema provisional; magnitud gráfica sin confirmación del fabricante","status":"derivado_del_esquema"},{"label":"Extensión de la malla en Z","value":0.10000000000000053,"unit":"m","source":"Malla del esquema provisional; magnitud gráfica sin confirmación del fabricante","status":"derivado_del_esquema"},{"label":"Cota inferior de visualización","value":290.35,"unit":"m","source":"Malla del esquema provisional; magnitud gráfica sin confirmación del fabricante","status":"datum_provisional"},{"label":"Cota superior de visualización","value":290.45,"unit":"m","source":"Malla del esquema provisional; magnitud gráfica sin confirmación del fabricante","status":"datum_provisional"}],"notes":["ESQUEMA PROVISIONAL · NO APTO PARA CONSTRUCCIÓN, FABRICACIÓN, COMPRA O MEDICIÓN. Las formas y dimensiones supuestas no están verificadas por el fabricante.","Las cotas y dimensiones del apoyo o ámbito documentado no confirman las dimensiones de los elementos superiores."]} | {"documentId":"CONCEPT-COORDINATION-20260908","title":"Esquema tridimensional provisional solicitado para coordinación visual","date":"2026-09-08","sheet":"Hipótesis de visualización; sin plano de fabricación","sourceScope":"Decisiones gráficas de modelado autorizadas; no incorpora dimensiones nuevas documentadas."} | {"segmentCenterModelM":[51.588617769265,48.99573174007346,5.4],"segmentAxis":[0.13620387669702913,0.9906808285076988,-0.0],"beamTopModelM":5.3500000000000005,"pipeBottomModelM":5.3500000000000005,"status":"Apoyo por contacto gráfico; sin detalle de abrazadera o zapata"} | ["ESQUEMA PROVISIONAL · NO APTO PARA CONSTRUCCIÓN, FABRICACIÓN, COMPRA O MEDICIÓN. Las formas y dimensiones supuestas no están verificadas por el fabricante.","No conectar a equipos ni utilizar como ruta de instalación. Las líneas no tienen identificación de fluido, presión, temperatura ni clase de tubería."] |  | {"boundingBoxM":{"min":[51.334778,47.5029,5.35],"max":[51.842458,50.488563,5.45]},"extentsM":[0.50768,2.985663,0.1],"meshSurfaceM2":0.955318,"meshVolumeM3":0.023294,"closedSolid":true,"basis":"Esquema provisional solicitado para coordinación visual. No apto para construcción, fabricación, compra o medición; las magnitudes de malla no son cantidades de obra."} | {"documentId":"LHD2609-JG00100-20260904","title":"Cimentaciones de equipos y pedestales del fabricante · revisión recibida 04/09/2026","date":"2026-09-04","sheet":"ZD1 / DZ-2","fileName":"LHD2609-JG00100_20260904.dwg","revisionCaveat":"Fecha de revisión tomada del nombre recibido; cajetines internos mantienen 02/07/2026 y algunos textos de plantilla.","sourceFileSha256":"b42eb027b7bc0b14c38d1d13514f4899b58a732aa8d0ba2ccf10fa2fc3192890"} | utilities | {"id":"utilities","name":"Servicios auxiliares"} | {"profileId":"concept_pipe","name":"Tramos de tubería · azul provisional","materialName":"No especificado","physicalMaterialStatus":"unknown","physicalMaterialSource":"Pendiente de documentación del fabricante","appearanceStatus":"esquema_provisional","appearanceBasis":"Color de identificación de geometría supuesta; no representa una especificación de acabado.","note":"Apariencia gráfica de hipótesis; no confirma el material físico."} | {"status":"objeto_independiente","note":"Parte del esquema seleccionable de forma independiente; no es un despiece de fabricación."} | {"elementId":"C33-CONCEPT-PIPE-02","ifcGuid":"0O2cZJU51I18tHMrJ6LctR","ifcClass":"IfcBuildingElementProxy","buildingId":"process_plant","buildingName":"Planta de proceso","sourceDocumentId":"CONCEPT-COORDINATION-20260908","sourceRepresentationKind":"conceptualVolume"} | {"layerId":"utilities","layerName":"Servicios auxiliares","role":"Tramo ilustrativo de tubería; servicio y ruta sin definir","basis":"Clasificación funcional del esquema, sin confirmar una configuración fabricada."} | {"profileId":"concept_pipe","name":"Tramos de tubería · azul provisional","status":"esquema_provisional","basis":"Color de identificación de geometría supuesta; no representa una especificación de acabado.","physicalMaterialUnchanged":true} |  | No especificado | Servicios auxiliares | Tramos de tubería · azul provisional | esquema_provisional | C33-CONCEPT-PIPE-02 | ["ESQUEMA PROVISIONAL · NO APTO PARA CONSTRUCCIÓN, FABRICACIÓN, COMPRA O MEDICIÓN. Las formas y dimensiones supuestas no están verificadas por el fabricante.", "No conectar a equipos ni utilizar como ruta de instalación. Las líneas no tienen identificación de fluido, presión, temperatura ni clase de tubería.", "GD05000 sitúa PT02 en E=16,000 m, N=21,400 m, coincidente en planta con el apoyo representado C33. GD06001 contiene dos láminas rotuladas PT01, con cotas superiores distintas. Correspondencia PT02/C33 y detalle aplicable pendientes: no sustituir el apoyo por una plataforma sin resolver esta discrepancia."] | Esquema provisional solicitado para coordinación visual. No apto para construcción, fabricación, compra o medición; las magnitudes de malla no son cantidades de obra. | No se han recibido especificaciones de este elemento. |  | yes | concept_pipe | [0.28,0.63,0.78] | 0.55 | 0.12 | Color de identificación de geometría supuesta; no representa una especificación de acabado. |  | BIM · Servicios auxiliares; Esquemas provisionales · no para construcción; C33 · soporte y dos tramos ilustrativos | JH_InformacionBIM - foundationIds: ["found_0904_d45da7c28766e5"]; heightStatus: illustrative_not_documented; quantityEligible: no; conceptual: {"enabled":true,"userRequestedProvisional3D":true,"basis":"Dos tramos cortos sin conexiones ilustran el uso posible de un soporte de tuberías. No son rutas de proceso ni confirman el número de líneas, su servicio, diámetro o cota real.","status":"illustrative_not_documented","physicalHeightConfirmed":false,"quantityEligible":false,"notForConstruction":true,"dimensionsNotDerivedFromPhotos":true,"warning":"ESQUEMA PROVISIONAL · NO APTO PARA CONSTRUCCIÓN, FABRICACIÓN, COMPRA O MEDICIÓN. Las formas y dimensiones supuestas no están verificadas por el fabricante."}; physicalHeightConfirmed: no; assemblyId: C33-CONCEPT; derivedFromFoundationId: found_0904_d45da7c28766e5; RevisionDocumentalComplementaria: {"fecha": "2026-09-09", "estado": "Revisión documental; geometría conservada", "criterio": "Documentación complementaria recibida el 09/09/2026. Tuberías: paquete actualizado el 07/08; fechas y revisiones por plano. La recepción no cambia la fecha de diseño. Se mantienen cargas del 25/08 y cimentaciones recibidas el 04/09 frente a las versiones anteriores incluidas.", "documentos": ["SOPC-PROCESS_019", "SOPC-PROCESS_028"], "conclusiones": ["GD05000 sitúa PT02 en E=16,000 m, N=21,400 m, coincidente en planta con el apoyo representado C33. GD06001 contiene dos láminas rotuladas PT01, con cotas superiores distintas. Correspondencia PT02/C33 y detalle aplicable pendientes: no sustituir el apoyo por una plataforma sin resolver esta discrepancia."]}; IncidenciasPendientes: ["ESQUEMA PROVISIONAL · NO APTO PARA CONSTRUCCIÓN, FABRICACIÓN, COMPRA O MEDICIÓN. Las formas y dimensiones supuestas no están verificadas por el fabricante.", "No conectar a equipos ni utilizar como ruta de instalación. Las líneas no tienen identificación de fluido, presión, temperatura ni clase de tubería.", "GD05000 sitúa PT02 en E=16,000 m, N=21,400 m, coincidente en planta con el apoyo representado C33. GD06001 contiene dos láminas rotuladas PT01, con cotas superiores distintas. Correspondencia PT02/C33 y detalle aplicable pendientes: no sustituir el apoyo por una plataforma sin resolver esta discrepancia."]; parentElementId: C33-CONCEPT-BEAM; connections: {"connected":false,"networkId":null,"service":"Desconocido","basis":"Tramo aislado de demostración; sin puertos ni conexiones de proceso definidos"}; JH_Trazabilidad - Identificador del objeto: C33-CONCEPT-PIPE-02; Estado de la información: Esquema provisional solicitado; Aplicabilidad a mediciones: No aplicable a mediciones, compras, fabricación o construcción.; Documento de origen: Esquema tridimensional provisional solicitado para coordinación visual; Alcance de la geometría: Tramo ilustrativo de tubería; servicio y ruta sin definir; Base documental y supuestos: Dos tramos cortos sin conexiones ilustran el uso posible de un soporte de tuberías. No son rutas de proceso ni confirman el número de líneas, su servicio, diámetro o cota real.; Aviso: ESQUEMA PROVISIONAL · NO APTO PARA CONSTRUCCIÓN, FABRICACIÓN, COMPRA O MEDICIÓN. Las formas y dimensiones supuestas no están verificadas por el fabricante.; RevisionDocumentalComplementaria: {"fecha": "2026-09-09", "estado": "Revisión documental; geometría conservada", "criterio": "Documentación complementaria recibida el 09/09/2026. Tuberías: paquete actualizado el 07/08; fechas y revisiones por plano. La recepción no cambia la fecha de diseño. Se mantienen cargas del 25/08 y cimentaciones recibidas el 04/09 frente a las versiones anteriores incluidas.", "documentos": ["SOPC-PROCESS_019", "SOPC-PROCESS_028"], "conclusiones": ["GD05000 sitúa PT02 en E=16,000 m, N=21,400 m, coincidente en planta con el apoyo representado C33. GD06001 contiene dos láminas rotuladas PT01, con cotas superiores distintas. Correspondencia PT02/C33 y detalle aplicable pendientes: no sustituir el apoyo por una plataforma sin resolver esta discrepancia."]}; JH_EsquemaProvisional - EsEsquema: yes; AptoParaConstruccion: no; IncluirEnMediciones: no; AlturaFisicaConfirmada: no; Criterio: Dos tramos cortos sin conexiones ilustran el uso posible de un soporte de tuberías. No son rutas de proceso ni confirman el número de líneas, su servicio, diámetro o cota real.; Advertencia: Esquema provisional solicitado para coordinación visual. No apto para construcción, fabricación, compra o medición; las magnitudes de malla no son cantidades de obra.; DimensionesSupuestas: [{"label":"Longitud ilustrativa del tramo","value":3.0,"unit":"m","source":"Elección gráfica, sin trazado documentado","status":"supuesto"},{"label":"Diámetro exterior ilustrativo","value":0.1,"unit":"m","source":"Elección gráfica; sin DN, espesor, material ni fluido confirmados","status":"supuesto"},{"label":"Separación entre ejes de los dos tramos","value":0.65,"unit":"m","source":"Elección gráfica","status":"supuesto"}]; JH_RevisionDocumental20260909 - Criterio: Documentación complementaria recibida el 09/09/2026. Tuberías: paquete actualizado el 07/08; fechas y revisiones por plano. La recepción no cambia la fecha de diseño. Se mantienen cargas del 25/08 y cimentaciones recibidas el 04/09 frente a las versiones anteriores incluidas.; Documentos: SOPC-PROCESS_019 | SOPC-PROCESS_028; Conclusiones: GD05000 sitúa PT02 en E=16,000 m, N=21,400 m, coincidente en planta con el apoyo representado C33. GD06001 contiene dos láminas rotuladas PT01, con cotas superiores distintas. Correspondencia PT02/C33 y detalle aplicable pendientes: no sustituir el apoyo por una plataforma sin resolver esta discrepancia.; GeometriaModificada: no

# IfcBuildingElementProxy: Envolvente acústica (3)
In: Parcela industrial Jinhong
Description: Envolvente acústica; PredefinedType: USERDEFINED; Document: Plano del fabricante: cargas de equipos; Group: Envolventes acústicas de equipos; Zona de separación de aire; BIM · Envolventes de equipos
JH_DimensionesDelModelo - Extensión de la malla en X: 5.84117 m; Extensión de la malla en Y: 9.25908 m; Extensión de la malla en Z: 5.2 m; Cota inferior del modelo: 286.1 m; Cota superior del modelo: 291.3 m
JH_MagnitudesGeometricas - ExtensionX: 5.84117 m; ExtensionY: 9.25908 m; ExtensionZ: 5.2 m; SuperficieDeLaMalla: 221.14 m2; VolumenGeometrico: 212.628 m3
JH_InformacionBIM - buildingId: process_plant; buildingName: Planta de proceso; level: Plataforma de equipos · base provisional 286,10 m; category: Envolvente acústica; ifcClass: IfcBuildingElementProxy; material: {"name":"No especificado","source":"Sin especificación de material en la documentación revisada","status":"unknown"}; source: {"documentId":"EQ-CARGAS-20260825","title":"Plano del fabricante: cargas de equipos","sheet":"Espacio modelo; número de plano no identificado","date":"2026-08-25"}; status: provisional; positioning: {"horizontalStatus":"derivado","verticalStatus":"provisional","baseElevationM":286.1,"note":"Base común provisional a cota 286,10 m tomada del vial próximo. Falta coordinar la cota de las cimentaciones y la superficie real de montaje. Coordenadas UTM obtenidas mediante el giro de implantación de −7,82824°."}; issues: ["Base común provisional a cota 286,10 m tomada del vial próximo. Falta coordinar la cota de las cimentaciones y la superficie real de montaje.","Envolvente completa de la cabina acústica; espesor, estructura y material no especificados."]; ifcAssociations: {"material":false,"document":true,"quantities":true,"containerGuid":"17utmjd_LKsAVvPyuSUhFt","containerName":"Parcela industrial Jinhong"}; visualLayer: {"id":"equipment_enclosures","name":"Envolventes de equipos"}; materialAppearance: {"profileId":"enclosure_acoustic","name":"Cabina acústica · gris claro provisional","materialName":"No especificado","physicalMaterialStatus":"unknown","physicalMaterialSource":"Sin especificación de material en la documentación revisada","appearanceStatus":"provisional","appearanceBasis":"Referencia visual de fotografías públicas de Jinhong Gas / fabricante. Apariencia provisional para coordinación; fotografías oficiales pueden orientar el color, pero no acreditan el material, el acabado ni el equipo concreto.","note":"La apariencia gráfica no modifica ni confirma la especificación física del material."}; classification: {"layerId":"equipment_enclosures","layerName":"Envolventes de equipos","role":"Envolvente acústica","basis":"Clasificación por función del elemento; no modifica las especificaciones documentales."}; layerId: equipment_enclosures; appearance: {"profileId":"enclosure_acoustic","name":"Cabina acústica · gris claro provisional","status":"provisional","basis":"Referencia visual de fotografías públicas de Jinhong Gas / fabricante. Apariencia provisional para coordinación; fotografías oficiales pueden orientar el color, pero no acreditan el material, el acabado ni el equipo concreto.","physicalMaterialUnchanged":true}
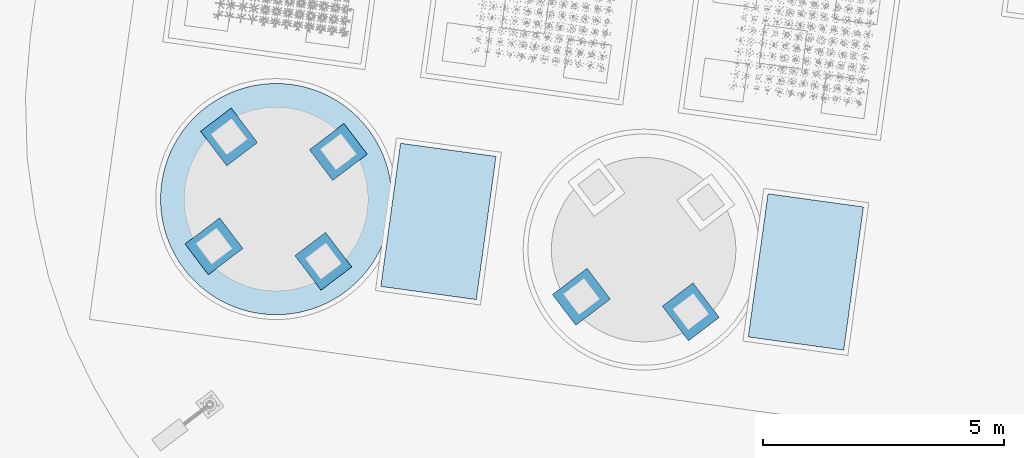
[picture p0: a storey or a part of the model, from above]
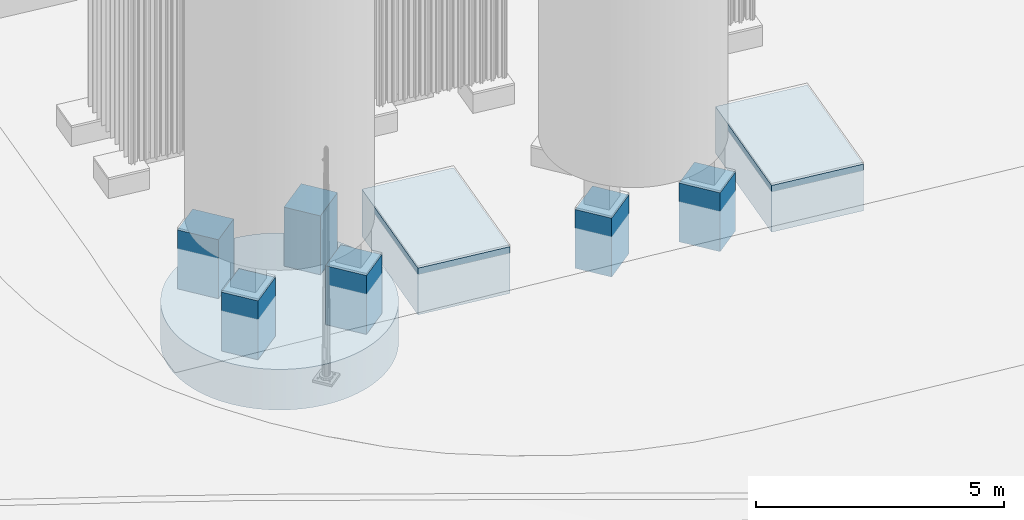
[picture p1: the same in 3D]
Properties of the parts of a building model (IFC4), part 53 of 134

# IfcBuildingElementProxy: Envolvente acústica (3)
JH_Trazabilidad - Referencia en el plano del fabricante: 1; Documento de origen: Plano del fabricante: cargas de equipos · 2026-08-25 · Espacio modelo; número de plano no identificado; Documento CAD derivado: Conversión DXF del plano de cargas de equipos · 2026-08-25 · espacio modelo; Capa CAD de referencia: Anotaciones y contornos de equipos; Cota de altura del fabricante (traducción): Altura del equipo: 5.2m; Altura (m): 5.2; Origen de las dimensiones: Plano de cargas del fabricante de 2026-08-25: lectura directa del contorno CAD cerrado y de la cota de altura del equipo.; Grado de definición: Contorno identificado y altura acotada explícitamente en el plano de cargas del fabricante.; Alcance de la geometría: Envolvente exterior del equipo; sin detalle constructivo interno.; Origen de la posición: Punto de referencia del fabricante: entidad CIRCLE, handle 98, en la esquina inferior izquierda de la zona de equipos. Los ejes X e Y son locales y se giran para su implantación UTM.; Hipótesis de modelado: La base local de cada equipo se generó en Z = 0 y se implantó provisionalmente a cota 286,10 m. Faltan coordinar cimentaciones y superficies de montaje. No se detallan fondos, interiores, boquillas ni espesores de chapa.; Observaciones: Contorno de la base de la cabina acústica identificado; representación mediante envolvente completa. Espesor constructivo sin especificar.; Masa propia indicada (kg): 6000; Dimensión X local (m): 4.7; Dimensión Y local (m): 8.7; Dimensiones de la plataforma de equipos (m): 27 × 57 m; dimensiones acotadas en el plano general.; Implantación de la plataforma de equipos: El punto de referencia del fabricante coincide con la esquina suroeste de la zona de equipos. Giro local de −7,82824° para la implantación en coordenadas UTM.; Estado de la cota de instalación: Cota de base provisional común de 286,10 m, tomada del vial próximo del plano general. Las cimentaciones y las superficies de montaje no están coordinadas; requiere comprobación.; Convención de coordenadas: Coordenadas locales del proyecto en metros. Añadir (729400, 4301550, 285) para recuperar las coordenadas UTM y las cotas del plano.; Disciplina: Envolventes acústicas de equipos; Clase IFC: IfcBuildingElementProxy; Fase del modelo: V0.1 · Reconstrucción a partir de planos y coordinación preliminar; Representación geométrica IFC: Sólido IFC4 mediante malla triangular cerrada; Aplicabilidad a mediciones: Los equipos se representan mediante envolventes. Los espesores y alturas supuestos y el volumen de las envolventes no representan cantidades de materiales, compras, construcción o fabricación.; Material: No especificado; Estado de la información: provisional; Capa BIM: Envolventes de equipos; Acabado de visualización: Cabina acústica · gris claro provisional; Estado del acabado: provisional; Categoria: Envolvente acústica; ClaseIFC: IfcBuildingElementProxy; EstadoDeInformacion: provisional; DocumentoFuente: {"documentId":"EQ-CARGAS-20260825","title":"Plano del fabricante: cargas de equipos","sheet":"Espacio modelo; número de plano no identificado","date":"2026-08-25"}; IncidenciasPendientes: ["Base común provisional a cota 286,10 m tomada del vial próximo. Falta coordinar la cota de las cimentaciones y la superficie real de montaje.","Envolvente completa de la cabina acústica; espesor, estructura y material no especificados."]; UsoDeLasMagnitudes: Geometría de coordinación. Los volúmenes de referencia y subcomponentes no son cantidades de material ni componentes de fabricación certificados.
JH_CriterioDePosicion - PosicionYEstado: {"horizontalStatus":"derivado","verticalStatus":"provisional","baseElevationM":286.1,"note":"Base común provisional a cota 286,10 m tomada del vial próximo. Falta coordinar la cota de las cimentaciones y la superficie real de montaje. Coordenadas UTM obtenidas mediante el giro de implantación de −7,82824°."}
JH_EvidenciaDeMaterial - name: No especificado; source: Sin especificación de material en la documentación revisada; status: unknown
JH_DimensionesDocumentadas - Dimensión X local del contorno CAD: 4.7 m; Dimensión Y local del contorno CAD: 8.7 m; Altura acotada: 5.2 m
JH_CapaBIM - IdentificadorCapa: equipment_enclosures; NombreCapa: Envolventes de equipos; Funcion: Envolvente acústica; VisibilidadInicial: yes
JH_AcabadoVisual - Perfil: enclosure_acoustic; Acabado: Cabina acústica · gris claro provisional; ColorRGB: [0.88,0.89,0.88]; Rugosidad: 0.48; Metallicidad: 0.18; Estado: provisional; Referencia: Referencia visual de fotografías públicas de Jinhong Gas / fabricante. Apariencia provisional para coordinación; fotografías oficiales pueden orientar el color, pero no acreditan el material, el acabado ni el equipo concreto.; Nota: La apariencia no certifica el material físico ni el acabado de fabricación.
Name | Reference = Identificador del fabricante o del modelo = Identificador del objeto = Identificador | dimensions | geometryMetrics | componentSeparation | visualizationIdentity | Identificadores CAD del contorno (handles) | Identificador CAD de la cota de altura (handle)
Cabina acústica de compresor AC-ENC-1 | AC-ENC-1 | {"documented":[{"label":"Dimensión X local del contorno CAD","value":4.7,"unit":"m","source":"EQ-CARGAS-20260825 · contorno CAD · handles B7","status":"derivado"},{"label":"Dimensión Y local del contorno CAD","value":8.7,"unit":"m","source":"EQ-CARGAS-20260825 · contorno CAD · handles B7","status":"derivado"},{"label":"Altura acotada","value":5.2,"unit":"m","source":"EQ-CARGAS-20260825 · handle 3F8","status":"documentado"}],"geometry":[{"label":"Extensión de la malla en X","value":5.841174,"unit":"m","source":"Calculada a partir de los vértices del modelo","status":"derivado"},{"label":"Extensión de la malla en Y","value":9.259082,"unit":"m","source":"Calculada a partir de los vértices del modelo","status":"derivado"},{"label":"Extensión de la malla en Z","value":5.2,"unit":"m","source":"Calculada a partir de los vértices del modelo","status":"derivado"},{"label":"Cota inferior del modelo","value":286.1,"unit":"m","source":"Coordenada Z mínima de la malla más origen vertical de 285 m","status":"derivado"},{"label":"Cota superior del modelo","value":291.3,"unit":"m","source":"Coordenada Z máxima de la malla más origen vertical de 285 m","status":"derivado"}],"notes":["Las extensiones de la malla se miden en los ejes del proyecto tras el giro de implantación; no sustituyen las dimensiones locales del fabricante.","La envolvente, su volumen y los espesores de visualización no son volúmenes de material ni cantidades de compra, construcción o fabricación.","Las dimensiones documentadas distinguen cotas explícitas y medidas extraídas de contornos CAD; las dimensiones geométricas describen únicamente la malla publicada."]} | {"boundingBoxM":{"min":[46.789721,68.698784,1.1],"max":[52.630895,77.957866,6.3]},"extentsM":[5.841174,9.259082,5.2],"meshSurfaceM2":221.140003,"meshVolumeM3":212.628005,"closedSolid":true,"basis":"Geometría triangulada releída del IFC; envolventes y magnitudes no contractuales."} | {"status":"envolvente_independiente","relatedEquipmentIds":["AC1001A"],"interiorEquipmentModeled":true,"note":"Cabina y compresor tienen IDs y mallas distintos. La cabina es una caja maciza de visualización; paredes y cubierta no están modeladas con espesor."} | {"elementId":"AC-ENC-1","ifcGuid":"3ZTwZym25VOwt6$sWL7FSj","ifcClass":"IfcBuildingElementProxy","buildingId":"process_plant","buildingName":"Planta de proceso","sourceDocumentId":"EQ-CARGAS-20260825","sourceRepresentationKind":"documentary_mesh"} | B7 | 3F8
Cabina acústica de compresor AC-ENC-2 | AC-ENC-2 | {"documented":[{"label":"Dimensión X local del contorno CAD","value":4.7,"unit":"m","source":"EQ-CARGAS-20260825 · contorno CAD · handles 53E","status":"derivado"},{"label":"Dimensión Y local del contorno CAD","value":8.7,"unit":"m","source":"EQ-CARGAS-20260825 · contorno CAD · handles 53E","status":"derivado"},{"label":"Altura acotada","value":5.2,"unit":"m","source":"EQ-CARGAS-20260825 · handle 25BF","status":"documentado"}],"geometry":[{"label":"Extensión de la malla en X","value":5.841174,"unit":"m","source":"Calculada a partir de los vértices del modelo","status":"derivado"},{"label":"Extensión de la malla en Y","value":9.259082,"unit":"m","source":"Calculada a partir de los vértices del modelo","status":"derivado"},{"label":"Extensión de la malla en Z","value":5.2,"unit":"m","source":"Calculada a partir de los vértices del modelo","status":"derivado"},{"label":"Cota inferior del modelo","value":286.1,"unit":"m","source":"Coordenada Z mínima de la malla más origen vertical de 285 m","status":"derivado"},{"label":"Cota superior del modelo","value":291.3,"unit":"m","source":"Coordenada Z máxima de la malla más origen vertical de 285 m","status":"derivado"}],"notes":["Las extensiones de la malla se miden en los ejes del proyecto tras el giro de implantación; no sustituyen las dimensiones locales del fabricante.","La envolvente, su volumen y los espesores de visualización no son volúmenes de material ni cantidades de compra, construcción o fabricación.","Las dimensiones documentadas distinguen cotas explícitas y medidas extraídas de contornos CAD; las dimensiones geométricas describen únicamente la malla publicada."]} | {"boundingBoxM":{"min":[53.130078,67.827079,1.1],"max":[58.971252,77.086161,6.3]},"extentsM":[5.841174,9.259082,5.2],"meshSurfaceM2":221.139998,"meshVolumeM3":212.627994,"closedSolid":true,"basis":"Geometría triangulada releída del IFC; envolventes y magnitudes no contractuales."} | {"status":"envolvente_independiente","relatedEquipmentIds":["AC1001B"],"interiorEquipmentModeled":true,"note":"Cabina y compresor tienen IDs y mallas distintos. La cabina es una caja maciza de visualización; paredes y cubierta no están modeladas con espesor."} | {"elementId":"AC-ENC-2","ifcGuid":"1oowuLfRPV4uM4Em7ULbj2","ifcClass":"IfcBuildingElementProxy","buildingId":"process_plant","buildingName":"Planta de proceso","sourceDocumentId":"EQ-CARGAS-20260825","sourceRepresentationKind":"documentary_mesh"} | 53E | 25BF
Cabina acústica de compresor AC-ENC-3 | AC-ENC-3 | {"documented":[{"label":"Dimensión X local del contorno CAD","value":4.7,"unit":"m","source":"EQ-CARGAS-20260825 · contorno CAD · handles 53F","status":"derivado"},{"label":"Dimensión Y local del contorno CAD","value":8.7,"unit":"m","source":"EQ-CARGAS-20260825 · contorno CAD · handles 53F","status":"derivado"},{"label":"Altura acotada","value":5.2,"unit":"m","source":"EQ-CARGAS-20260825 · handle 25CF","status":"documentado"}],"geometry":[{"label":"Extensión de la malla en X","value":5.841174,"unit":"m","source":"Calculada a partir de los vértices del modelo","status":"derivado"},{"label":"Extensión de la malla en Y","value":9.259082,"unit":"m","source":"Calculada a partir de los vértices del modelo","status":"derivado"},{"label":"Extensión de la malla en Z","value":5.2,"unit":"m","source":"Calculada a partir de los vértices del modelo","status":"derivado"},{"label":"Cota inferior del modelo","value":286.1,"unit":"m","source":"Coordenada Z mínima de la malla más origen vertical de 285 m","status":"derivado"},{"label":"Cota superior del modelo","value":291.3,"unit":"m","source":"Coordenada Z máxima de la malla más origen vertical de 285 m","status":"derivado"}],"notes":["Las extensiones de la malla se miden en los ejes del proyecto tras el giro de implantación; no sustituyen las dimensiones locales del fabricante.","La envolvente, su volumen y los espesores de visualización no son volúmenes de material ni cantidades de compra, construcción o fabricación.","Las dimensiones documentadas distinguen cotas explícitas y medidas extraídas de contornos CAD; las dimensiones geométricas describen únicamente la malla publicada."]} | {"boundingBoxM":{"min":[59.470436,66.955374,1.1],"max":[65.31161,76.214456,6.3]},"extentsM":[5.841174,9.259082,5.2],"meshSurfaceM2":221.14001,"meshVolumeM3":212.628014,"closedSolid":true,"basis":"Geometría triangulada releída del IFC; envolventes y magnitudes no contractuales."} | {"status":"envolvente_independiente","relatedEquipmentIds":["AC1001C"],"interiorEquipmentModeled":true,"note":"Cabina y compresor tienen IDs y mallas distintos. La cabina es una caja maciza de visualización; paredes y cubierta no están modeladas con espesor."} | {"elementId":"AC-ENC-3","ifcGuid":"1RT83N82rJWxMhnTRpZUpf","ifcClass":"IfcBuildingElementProxy","buildingId":"process_plant","buildingName":"Planta de proceso","sourceDocumentId":"EQ-CARGAS-20260825","sourceRepresentationKind":"documentary_mesh"} | 53F | 25CF

# IfcBuildingElementProxy: Envolvente conceptual de caja fría, Caja fría de la columna principal · aproximadamente 30 m, pendiente de confirmar
In: Parcela industrial Jinhong
Description: Envolvente conceptual de caja fría; PredefinedType: USERDEFINED; Document: Plano del fabricante: implantación de equipos · referencia E7; Cimentaciones de equipos y pedestales del fabricante · revisión recibida 04/09/2026; Fotografía de referencia aportada · 01; Fotografía de referencia aportada · 02; Fotografía de referencia aportada · 03; Fotografía de referencia aportada · 04; Soportes de equipos SL1201 y SL401/402; Planta de estructuras metálicas; Plantas generales de instrumentación; Alumbrado de la caja fría; Group: Equipos; Zona de separación de aire; BIM · Envolventes de equipos
Pset_BuildingElementProxyCommon - Reference: CB-MAIN
JH_DimensionesDelModelo - Extensión de la malla en X: 4.04552 m; Extensión de la malla en Y: 4.04552 m; Extensión de la malla en Z: 30 m; Cota inferior de visualización: 286.2 m; Cota superior de visualización: 316.2 m
JH_MagnitudesGeometricas - ExtensionX: 4.04552 m; ExtensionY: 4.04552 m; ExtensionZ: 30 m; SuperficieDeLaMalla: 456.577 m2; VolumenGeometrico: 386.644 m3
JH_CoordinacionCimentaciones - ElementosDeCimentacion: ["found_0904_f7e6bebab60859","found_0904_ab1632a7d9dd78","found_0904_e82a8a5ec7336e","found_0904_323dc0fbe26a0b","found_0904_3aab66a70a9bd0","found_0904_33c531229e93fa"]; Relacion: Correspondencia documental; no verifica anclajes ni cotas de montaje.
JH_CapaBIM - IdentificadorCapa: equipment_enclosures; NombreCapa: Envolventes de equipos; Funcion: Envolvente conceptual de caja fría; VisibilidadInicial: yes
JH_AcabadoVisual - Perfil: enclosure_cold_box; Acabado: Caja fría · blanco satinado de referencia; ColorRGB: [0.925,0.93,0.915]; Rugosidad: 0.5; Metallicidad: 0.12; Estado: referencia_fotografica_provisional; Referencia: Fotografías reales aportadas el 08/09/2026, sin fecha de toma ni emplazamiento verificados. Caras blancas satinadas visibles en las fotografías 01, 02, 03 y 04; plataformas y escaleras exteriores visibles, sin dimensiones del proyecto. Tono y parámetros de visualización orientativos; no especifican pintura, aleación ni dimensiones.; Nota: La apariencia no certifica el material físico ni el acabado de fabricación.; Fotografias: ["jinhong-official-asu","foto-usuario-20260908-01","foto-usuario-20260908-02","foto-usuario-20260908-03","foto-usuario-20260908-04"]; FechaRevision: 2026-09-08
JH_RevisionDocumental20260909 - Criterio: Documentación complementaria recibida el 09/09/2026. Tuberías: paquete actualizado el 07/08; fechas y revisiones por plano. La recepción no cambia la fecha de diseño. Se mantienen cargas del 25/08 y cimentaciones recibidas el 04/09 frente a las versiones anteriores incluidas.; Documentos: SOPC-PROCESS_020 | SOPC-PROCESS_019 | SOPC-INSTRUMENT_002; Conclusiones: GD05001, lámina 2: +3,800 m corresponde al techo de la caja de paso del expansor; +6,050 m al soporte SL401/402; +0,100 m al apoyo inferior. No equivalen a las alturas físicas de los expansores. Relación con cada envolvente del modelo pendiente de confirmar; se conservan los volúmenes provisionales.; GeometriaModificada: no
JH_InformacionBIM - buildingId: process_plant; buildingName: Planta de proceso; level: Apoyo relativo +0.100 m; cero absoluto provisional; category: Envolvente conceptual de caja fría; ifcClass: IfcBuildingElementProxy; material: {"name":"No especificado","source":"Sin especificación de material en la documentación revisada","status":"unknown"}; dimensions: {"documented":[{"label":"Dimensión X local del contorno CAD","value":3.590002,"unit":"m","source":"EQ-IMPLANTACION-20260430 · contorno CAD · handles 91452,91453,91471,91599","status":"derivado"},{"label":"Dimensión Y local del contorno CAD","value":3.590003,"unit":"m","source":"EQ-IMPLANTACION-20260430 · contorno CAD · handles 91452,91453,91471,91599","status":"derivado"},{"label":"Cota relativa de la superficie de apoyo","value":0.1,"unit":"m","source":"LHD2609-JG00100-20260904 · sección 4 / 4-4 / 4a-4a · 1FE9E, 1FF16, 1FF22","status":"documentado"}],"geometry":[{"label":"Extensión de la malla en X","value":4.045518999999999,"unit":"m","source":"Geometría releída del IFC; datum absoluto de proceso provisional","status":"derivado"},{"label":"Extensión de la malla en Y","value":4.045520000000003,"unit":"m","source":"Geometría releída del IFC; datum absoluto de proceso provisional","status":"derivado"},{"label":"Extensión de la malla en Z","value":30.0,"unit":"m","source":"Geometría releída del IFC; datum absoluto de proceso provisional","status":"derivado"},{"label":"Cota inferior de visualización","value":286.20000000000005,"unit":"m","source":"Geometría releída del IFC; datum absoluto de proceso provisional","status":"derivado"},{"label":"Cota superior de visualización","value":316.20000000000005,"unit":"m","source":"Geometría releída del IFC; datum absoluto de proceso provisional","status":"derivado"}],"notes":["Las extensiones de la malla se miden en los ejes del proyecto tras el giro de implantación; no sustituyen las dimensiones locales del fabricante.","La envolvente, su volumen y los espesores de visualización no son volúmenes de material ni cantidades de compra, construcción o fabricación.","Las dimensiones documentadas distinguen cotas explícitas y medidas extraídas de contornos CAD; las dimensiones geométricas describen únicamente la malla publicada."]}; source: {"documentId":"EQ-IMPLANTACION-20260430","title":"Plano del fabricante: implantación de equipos · referencia E7","sheet":"Espacio modelo; referencia E7 en el nombre del archivo","date":"2026-04-30"}; status: provisional; positioning: {"Estado de la planta":"Derivado del CAD y del giro de implantación","Nivel relativo del apoyo (m)":0.1,"Estado del nivel relativo":"Documentado en el plano de cimentaciones","Cero absoluto de visualización (m)":286.1,"Estado del cero absoluto":"Provisional","Cota del apoyo de visualización (m)":286.20000000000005,"Desplazamiento aplicado a la malla (m)":0.10000000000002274,"Criterio":"Nivel de apoyo relativo documentado. Se adopta el cero de proceso a 286,10 m solo para visualización; la equivalencia absoluta no está confirmada. No se añade un espesor de montaje sin cota del fabricante."}; issues: ["Altura aproximada de 30 m basada en una estimación verbal ambigua; pendiente de alzado o plano dimensional oficial. No utilizar para conclusiones de gálibo, interferencias, construcción o transporte.","Cota de la plataforma elevada +0,100; losa exterior a 0,000. La relación XY de cada subcaja con la plataforma elevada debe verificarse en el modelo final.","Fondo ambiguo: sección 4-4 indica -1,000 pero cotas 1500 mm y sección 4a-4a indican -1,500.","El cero absoluto de la revisión no está definido; 286,10 m sigue siendo una hipótesis de coordinación.","Se alinea el punto inferior del conjunto del equipo, incluidos los pies ya representados, con la superficie de apoyo terminada; no se añade un espesor de calzos, placa o grout del fabricante no documentado.","GD05001, lámina 2: +3,800 m corresponde al techo de la caja de paso del expansor; +6,050 m al soporte SL401/402; +0,100 m al apoyo inferior. No equivalen a las alturas físicas de los expansores. Relación con cada envolvente del modelo pendiente de confirmar; se conservan los volúmenes provisionales.","DQ05000 H1 contiene cuatro alzados de alumbrado y LAMP1–15. El texto chino indica poste de 2,0 m y el inglés 2,5 m: discrepancia pendiente. Los alzados sin cotas no confirman la altura total del equipo ni los niveles de plataformas."]; geometryMetrics: {"boundingBoxM":{"min":[53.149521,38.717931,1.2],"max":[57.19504,42.763451,31.2]},"extentsM":[4.045519,4.04552,30.0],"meshSurfaceM2":456.576529,"meshVolumeM3":386.643528,"closedSolid":true,"basis":"Magnitudes de las mallas representadas, no cantidades certificadas de obra, compra o fabricación. Las partes pueden compartir superficies; no se suman como un despiece de materiales."}; ifcAssociations: {"material":false,"document":true,"quantities":true,"containerGuid":"17utmjd_LKsAVvPyuSUhFt","containerName":"Parcela industrial Jinhong"}; installationSource: {"documentId":"LHD2609-JG00100-20260904","title":"Cimentaciones y pedestales de equipos · revisión recibida 04/09/2026","date":"2026-09-04","sheet":"4 / 4-4 / 4a-4a","sourceHandles":["1FE9E","1FF16","1FF22"]}; representationKind: equipment; foundationIds: ["found_0904_f7e6bebab60859","found_0904_ab1632a7d9dd78","found_0904_e82a8a5ec7336e","found_0904_323dc0fbe26a0b","found_0904_3aab66a70a9bd0","found_0904_33c531229e93fa"]; visualLayer: {"id":"equipment_enclosures","name":"Envolventes de equipos"}; materialAppearance: {"profileId":"enclosure_cold_box","name":"Caja fría · blanco satinado de referencia","materialName":"No especificado","physicalMaterialStatus":"unknown","physicalMaterialSource":"Sin especificación de material en la documentación revisada","appearanceStatus":"referencia_fotografica_provisional","appearanceBasis":"Fotografías reales aportadas el 08/09/2026, sin fecha de toma ni emplazamiento verificados. Caras blancas satinadas visibles en las fotografías 01, 02, 03 y 04; plataformas y escaleras exteriores visibles, sin dimensiones del proyecto. Tono y parámetros de visualización orientativos; no especifican pintura, aleación ni dimensiones.","note":"La apariencia gráfica no modifica ni confirma la especificación física del material."}; componentSeparation: {"status":"envolvente_independiente_sin_interiores","interiorEquipmentModeled":false,"note":"Envolvente exterior completa en un objeto. Paneles, accesos y equipos internos no están separados ni documentados como geometría independiente."}; visualizationIdentity: {"elementId":"CB-MAIN","ifcGuid":"3TUYYRIxPGkvd2wWdAvlFb","ifcClass":"IfcBuildingElementProxy","buildingId":"process_plant","buildingName":"Planta de proceso","sourceDocumentId":"EQ-IMPLANTACION-20260430","sourceRepresentationKind":"equipment"}; classification: {"layerId":"equipment_enclosures","layerName":"Envolventes de equipos","role":"Envolvente conceptual de caja fría","basis":"Clasificación por función del elemento; no modifica las especificaciones documentales."}; layerId: equipment_enclosures; appearance: {"profileId":"enclosure_cold_box","name":"Caja fría · blanco satinado de referencia","status":"referencia_fotografica_provisional","basis":"Fotografías reales aportadas el 08/09/2026, sin fecha de toma ni emplazamiento verificados. Caras blancas satinadas visibles en las fotografías 01, 02, 03 y 04; plataformas y escaleras exteriores visibles, sin dimensiones del proyecto. Tono y parámetros de visualización orientativos; no especifican pintura, aleación ni dimensiones.","physicalMaterialUnchanged":true}; photoAppearanceReview: {"receivedDate":"2026-09-08","referenceIds":["jinhong-official-asu","foto-usuario-20260908-01","foto-usuario-20260908-02","foto-usuario-20260908-03","foto-usuario-20260908-04"],"use":"Color, brillo y lectura de superficies. Sin cambios de geometría o dimensiones.","geometryConfirmedByPhotos":false}; supplementaryDrawingReview: {"fecha":"2026-09-09","estado":"Revisión documental; geometría conservada","criterio":"Documentación complementaria recibida el 09/09/2026. Tuberías: paquete actualizado el 07/08; fechas y revisiones por plano. La recepción no cambia la fecha de diseño. Se mantienen cargas del 25/08 y cimentaciones recibidas el 04/09 frente a las versiones anteriores incluidas.","documentos":["SOPC-PROCESS_020","SOPC-PROCESS_019","SOPC-INSTRUMENT_002","SOPC-ELECTRICAL_003"],"conclusiones":["GD05001, lámina 2: +3,800 m corresponde al techo de la caja de paso del expansor; +6,050 m al soporte SL401/402; +0,100 m al apoyo inferior. No equivalen a las alturas físicas de los expansores. Relación con cada envolvente del modelo pendiente de confirmar; se conservan los volúmenes provisionales.","DQ05000 H1 contiene cuatro alzados de alumbrado y LAMP1–15. El texto chino indica poste de 2,0 m y el inglés 2,5 m: discrepancia pendiente. Los alzados sin cotas no confirman la altura total del equipo ni los niveles de plataformas."]}
JH_Trazabilidad - Referencia en el plano del fabricante: 4; Grado de definición: Altura de aproximadamente 30 m procedente de una estimación verbal, pendiente de confirmar mediante alzado o plano dimensional oficial del fabricante.; Hipótesis de modelado: Nivel de apoyo relativo documentado. Se adopta el cero de proceso a 286,10 m solo para visualización; la equivalencia absoluta no está confirmada. No se añade un espesor de montaje sin cota del fabricante.; Documento de origen: Plano del fabricante: implantación de equipos · referencia E7 · 2026-04-30 · Espacio modelo; referencia E7 en el nombre del archivo; Bloque CAD: 14257432; Identificador CAD de la inserción (handle): 9122B; Identificadores CAD del contorno (handles): 91452,91453,91471,91599; Identificador CAD del rótulo (handle): 9159B; Origen de las dimensiones: Contorno del equipo representado con línea de doble trazo y punto dentro del bloque CAD activo del fabricante. El contorno grueso exterior corresponde a la cimentación y no se adopta como envolvente del equipo.; Origen de la altura: Estimación verbal de aproximadamente 30 m en la reunión de 2026-07-20, 16:48:07, párrafo 813. La transcripción numérica es ambigua y no constituye una cota de plano.; Alcance de la geometría: Volumen conceptual basado en una altura estimada verbalmente; Dimensión X local del contorno (m): 3.59; Dimensión Y local del contorno (m): 3.59; Fiabilidad de la altura: Estimación verbal; pendiente de confirmación documental; Altura (m): 30; Dimensiones de la plataforma de equipos (m): 27 × 57 m; dimensiones acotadas en el plano general.; Implantación de la plataforma de equipos: El punto de referencia del fabricante coincide con la esquina suroeste de la zona de equipos. Giro local de −7,82824° para la implantación en coordenadas UTM.; Estado de la cota de instalación: Nivel de apoyo relativo documentado. Se adopta el cero de proceso a 286,10 m solo para visualización; la equivalencia absoluta no está confirmada. No se añade un espesor de montaje sin cota del fabricante.; Convención de coordenadas: Coordenadas locales del proyecto en metros. Añadir (729400, 4301550, 285) para recuperar las coordenadas UTM y las cotas del plano.; Identificador del objeto: CB-MAIN; Disciplina: Equipos; Clase IFC: IfcBuildingElementProxy; Fase del modelo: Revisión de la zona de separación de aire · septiembre de 2026; Representación geométrica IFC: Sólido IFC4 mediante malla triangular cerrada; Aplicabilidad a mediciones: Los equipos se representan mediante envolventes. Los espesores y alturas supuestos y el volumen de las envolventes no representan cantidades de materiales, compras, construcción o fabricación.; Material: No especificado; Estado de la información: provisional; Nivel relativo de apoyo documentado (m): 0.1; Fuente del nivel de apoyo: {"documentId":"LHD2609-JG00100-20260904","title":"Cimentaciones y pedestales de equipos · revisión recibida 04/09/2026","date":"2026-09-04","sheet":"4 / 4-4 / 4a-4a","sourceHandles":["1FE9E","1FF16","1FF22"]}; Criterio de instalación: Nivel de apoyo relativo documentado. Se adopta el cero de proceso a 286,10 m solo para visualización; la equivalencia absoluta no está confirmada. No se añade un espesor de montaje sin cota del fabricante.; Capa BIM: Envolventes de equipos; Acabado de visualización: Caja fría · blanco satinado de referencia; Estado del acabado: referencia_fotografica_provisional; Revisión documental complementaria: {"fecha":"2026-09-09","estado":"Revisión documental; geometría conservada","criterio":"Documentación complementaria recibida el 09/09/2026. Tuberías: paquete actualizado el 07/08; fechas y revisiones por plano. La recepción no cambia la fecha de diseño. Se mantienen cargas del 25/08 y cimentaciones recibidas el 04/09 frente a las versiones anteriores incluidas.","documentos":["SOPC-PROCESS_020","SOPC-PROCESS_019","SOPC-INSTRUMENT_002"],"conclusiones":["GD05001, lámina 2: +3,800 m corresponde al techo de la caja de paso del expansor; +6,050 m al soporte SL401/402; +0,100 m al apoyo inferior. No equivalen a las alturas físicas de los expansores. Relación con cada envolvente del modelo pendiente de confirmar; se conservan los volúmenes provisionales."]}; Identificador: CB-MAIN; Categoria: Envolvente conceptual de caja fría; ClaseIFC: IfcBuildingElementProxy; EstadoDeInformacion: provisional; DocumentoFuente: {"documentId":"EQ-IMPLANTACION-20260430","title":"Plano del fabricante: implantación de equipos · referencia E7","sheet":"Espacio modelo; referencia E7 en el nombre del archivo","date":"2026-04-30"}; IncidenciasPendientes: ["Altura aproximada de 30 m basada en una estimación verbal ambigua; pendiente de alzado o plano dimensional oficial. No utilizar para conclusiones de gálibo, interferencias, construcción o transporte.","Cota de la plataforma elevada +0,100; losa exterior a 0,000. La relación XY de cada subcaja con la plataforma elevada debe verificarse en el modelo final.","Fondo ambiguo: sección 4-4 indica -1,000 pero cotas 1500 mm y sección 4a-4a indican -1,500.","El cero absoluto de la revisión no está definido; 286,10 m sigue siendo una hipótesis de coordinación.","Se alinea el punto inferior del conjunto del equipo, incluidos los pies ya representados, con la superficie de apoyo terminada; no se añade un espesor de calzos, placa o grout del fabricante no documentado.","GD05001, lámina 2: +3,800 m corresponde al techo de la caja de paso del expansor; +6,050 m al soporte SL401/402; +0,100 m al apoyo inferior. No equivalen a las alturas físicas de los expansores. Relación con cada envolvente del modelo pendiente de confirmar; se conservan los volúmenes provisionales.","DQ05000 H1 contiene cuatro alzados de alumbrado y LAMP1–15. El texto chino indica poste de 2,0 m y el inglés 2,5 m: discrepancia pendiente. Los alzados sin cotas no confirman la altura total del equipo ni los niveles de plataformas."]; UsoDeLasMagnitudes: Geometría de coordinación basada en planos recibidos; no sustituye el modelo de fabricación ni una medición certificada. Datum absoluto de proceso provisional.
JH_CriterioDePosicion - PosicionYEstado: {"Estado de la planta":"Derivado del CAD y del giro de implantación","Nivel relativo del apoyo (m)":0.1,"Estado del nivel relativo":"Documentado en el plano de cimentaciones","Cero absoluto de visualización (m)":286.1,"Estado del cero absoluto":"Provisional","Cota del apoyo de visualización (m)":286.20000000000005,"Desplazamiento aplicado a la malla (m)":0.10000000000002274,"Criterio":"Nivel de apoyo relativo documentado. Se adopta el cero de proceso a 286,10 m solo para visualización; la equivalencia absoluta no está confirmada. No se añade un espesor de montaje sin cota del fabricante."}
JH_EvidenciaDeMaterial - name: No especificado; source: Sin especificación de material en la documentación revisada; status: unknown
JH_DimensionesDocumentadas - Dimensión X local del contorno CAD: 3.59 m; Dimensión Y local del contorno CAD: 3.59 m; Cota relativa de la superficie de apoyo: 0.1 m

# IfcBuildingElementProxy: Envolvente de equipo (5)
In: Parcela industrial Jinhong
Description: Envolvente de equipo; PredefinedType: USERDEFINED; Document: Plano del fabricante: cargas de equipos; Cimentaciones de equipos y pedestales del fabricante · revisión recibida 04/09/2026; Group: Equipos; Zona de separación de aire; BIM · Envolventes de equipos
JH_CoordinacionCimentaciones - Relacion: Correspondencia documental; no verifica anclajes ni cotas de montaje.
JH_InformacionBIM - buildingId: process_plant; buildingName: Planta de proceso; category: Envolvente de equipo; ifcClass: IfcBuildingElementProxy; material: {"name":"No especificado","source":"Sin especificación de material en la documentación revisada","status":"unknown"}; source: {"documentId":"EQ-CARGAS-20260825","title":"Plano del fabricante: cargas de equipos","sheet":"Espacio modelo; número de plano no identificado","date":"2026-08-25"}; status: provisional; ifcAssociations: {"material":false,"document":true,"quantities":true,"containerGuid":"17utmjd_LKsAVvPyuSUhFt","containerName":"Parcela industrial Jinhong"}; representationKind: equipment; visualLayer: {"id":"equipment_enclosures","name":"Envolventes de equipos"}; materialAppearance: {"profileId":"enclosure_container","name":"Módulo técnico · gris blanco provisional","materialName":"No especificado","physicalMaterialStatus":"unknown","physicalMaterialSource":"Sin especificación de material en la documentación revisada","appearanceStatus":"provisional","appearanceBasis":"Referencia visual de fotografías públicas de Jinhong Gas / fabricante. Apariencia provisional para coordinación; fotografías oficiales pueden orientar el color, pero no acreditan el material, el acabado ni el equipo concreto.","note":"La apariencia gráfica no modifica ni confirma la especificación física del material."}; componentSeparation: {"status":"envolvente_independiente_sin_interiores","interiorEquipmentModeled":false,"note":"Envolvente exterior completa en un objeto. Paneles, accesos y equipos internos no están separados ni documentados como geometría independiente."}; classification: {"layerId":"equipment_enclosures","layerName":"Envolventes de equipos","role":"Envolvente de equipo","basis":"Clasificación por función del elemento; no modifica las especificaciones documentales."}; layerId: equipment_enclosures; appearance: {"profileId":"enclosure_container","name":"Módulo técnico · gris blanco provisional","status":"provisional","basis":"Referencia visual de fotografías públicas de Jinhong Gas / fabricante. Apariencia provisional para coordinación; fotografías oficiales pueden orientar el color, pero no acreditan el material, el acabado ni el equipo concreto.","physicalMaterialUnchanged":true}
JH_Trazabilidad - Documento de origen: Plano del fabricante: cargas de equipos · 2026-08-25 · Espacio modelo; número de plano no identificado; Documento CAD derivado: Conversión DXF del plano de cargas de equipos · 2026-08-25 · espacio modelo; Capa CAD de referencia: Anotaciones y contornos de equipos; Origen de las dimensiones: Plano de cargas del fabricante de 2026-08-25: lectura directa del contorno CAD cerrado y de la cota de altura del equipo.; Grado de definición: Contorno identificado y altura acotada explícitamente en el plano de cargas del fabricante.; Alcance de la geometría: Envolvente exterior del equipo; sin detalle constructivo interno.; Origen de la posición: Punto de referencia del fabricante: entidad CIRCLE, handle 98, en la esquina inferior izquierda de la zona de equipos. Los ejes X e Y son locales y se giran para su implantación UTM.; Hipótesis de modelado: Nivel de apoyo relativo documentado. Se adopta el cero de proceso a 286,10 m solo para visualización; la equivalencia absoluta no está confirmada. No se añade un espesor de montaje sin cota del fabricante.; Dimensiones de la plataforma de equipos (m): 27 × 57 m; dimensiones acotadas en el plano general.; Implantación de la plataforma de equipos: El punto de referencia del fabricante coincide con la esquina suroeste de la zona de equipos. Giro local de −7,82824° para la implantación en coordenadas UTM.; Estado de la cota de instalación: Nivel de apoyo relativo documentado. Se adopta el cero de proceso a 286,10 m solo para visualización; la equivalencia absoluta no está confirmada. No se añade un espesor de montaje sin cota del fabricante.; Convención de coordenadas: Coordenadas locales del proyecto en metros. Añadir (729400, 4301550, 285) para recuperar las coordenadas UTM y las cotas del plano.; Disciplina: Equipos; Clase IFC: IfcBuildingElementProxy; Fase del modelo: Revisión de la zona de separación de aire · septiembre de 2026; Representación geométrica IFC: Sólido IFC4 mediante malla triangular cerrada; Aplicabilidad a mediciones: Los equipos se representan mediante envolventes. Los espesores y alturas supuestos y el volumen de las envolventes no representan cantidades de materiales, compras, construcción o fabricación.; Material: No especificado; Estado de la información: provisional; Criterio de instalación: Nivel de apoyo relativo documentado. Se adopta el cero de proceso a 286,10 m solo para visualización; la equivalencia absoluta no está confirmada. No se añade un espesor de montaje sin cota del fabricante.; Capa BIM: Envolventes de equipos; Acabado de visualización: Módulo técnico · gris blanco provisional; Estado del acabado: provisional; Categoria: Envolvente de equipo; ClaseIFC: IfcBuildingElementProxy; EstadoDeInformacion: provisional; DocumentoFuente: {"documentId":"EQ-CARGAS-20260825","title":"Plano del fabricante: cargas de equipos","sheet":"Espacio modelo; número de plano no identificado","date":"2026-08-25"}; UsoDeLasMagnitudes: Geometría de coordinación. Los volúmenes de referencia y subcomponentes no son cantidades de material ni componentes de fabricación certificados.
JH_EvidenciaDeMaterial - name: No especificado; source: Sin especificación de material en la documentación revisada; status: unknown
JH_CapaBIM - IdentificadorCapa: equipment_enclosures; NombreCapa: Envolventes de equipos; Funcion: Envolvente de equipo; VisibilidadInicial: yes
JH_AcabadoVisual - Perfil: enclosure_container; Acabado: Módulo técnico · gris blanco provisional; ColorRGB: [0.88,0.89,0.88]; Rugosidad: 0.5; Metallicidad: 0.2; Estado: provisional; Referencia: Referencia visual de fotografías públicas de Jinhong Gas / fabricante. Apariencia provisional para coordinación; fotografías oficiales pueden orientar el color, pero no acreditan el material, el acabado ni el equipo concreto.; Nota: La apariencia no certifica el material físico ni el acabado de fabricación.
Name | Reference = Identificador del fabricante o del modelo = Identificador del objeto = Identificador | Extensión de la malla en X (m) = ExtensionX (m) | Extensión de la malla en Y (m) = ExtensionY (m) | Extensión de la malla en Z (m) = ExtensionZ (m) = Altura (m) = Altura acotada (m) | Cota inferior de visualización (m) | Cota superior de visualización (m) | SuperficieDeLaMalla (m2) | VolumenGeometrico (m3) | ElementosDeCimentacion = foundationIds | level | dimensions | positioning = PosicionYEstado | issues = IncidenciasPendientes | geometryMetrics | installationSource = Fuente del nivel de apoyo | visualizationIdentity | Referencia en el plano del fabricante | Identificadores CAD del contorno (handles) | Identificador CAD de la cota de altura (handle) | Cota de altura del fabricante (traducción) | Masa propia indicada (kg) | Dimensión X local (m) = Dimensión X local del contorno CAD (m) | Dimensión Y local (m) = Dimensión Y local del contorno CAD (m) | Nivel relativo de apoyo documentado (m) = Cota relativa de la superficie de apoyo (m)
Módulo de distribución eléctrica de baja tensión LV-CONTAINER | LV-CONTAINER | 4.13659 | 8.87893 | 3.3 | 287.6 | 290.9 | 127.53 | 84.645 | ["found_0904_ea077e07e4c91b","found_0904_6624999f1865f2","found_0904_12e1ff91ca7419","found_0904_ddf6874c317c25","found_0904_54183cb465992b","found_0904_703548d0d1268f","found_0904_b3a9a2c40a9ee0","found_0904_7f9093c00ae6c1","found_0904_ac15fe863abb4f","found_0904_2a64ff58200521","found_0904_cbb8e054dcc1c6","found_0904_9050dd5e67c1f4","found_0904_56c01f6ad420ae","found_0904_dd36a5bcfb9508","found_0904_0b74fa43408488"] | Apoyo relativo +1.500 m; cero absoluto provisional | {"documented":[{"label":"Dimensión X local del contorno CAD","value":3.0,"unit":"m","source":"EQ-CARGAS-20260825 · contorno CAD · handles 507","status":"derivado"},{"label":"Dimensión Y local del contorno CAD","value":8.55,"unit":"m","source":"EQ-CARGAS-20260825 · contorno CAD · handles 507","status":"derivado"},{"label":"Altura acotada","value":3.3,"unit":"m","source":"EQ-CARGAS-20260825 · handle 2629","status":"documentado"},{"label":"Cota relativa de la superficie de apoyo","value":1.5,"unit":"m","source":"LHD2609-JG00100-20260904 · sección 13 / 13-13 · 1DE6F, 1DC50","status":"documentado"}],"geometry":[{"label":"Extensión de la malla en X","value":4.136586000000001,"unit":"m","source":"Geometría releída del IFC; datum absoluto de proceso provisional","status":"derivado"},{"label":"Extensión de la malla en Y","value":8.87893299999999,"unit":"m","source":"Geometría releída del IFC; datum absoluto de proceso provisional","status":"derivado"},{"label":"Extensión de la malla en Z","value":3.3000000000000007,"unit":"m","source":"Geometría releída del IFC; datum absoluto de proceso provisional","status":"derivado"},{"label":"Cota inferior de visualización","value":287.6,"unit":"m","source":"Geometría releída del IFC; datum absoluto de proceso provisional","status":"derivado"},{"label":"Cota superior de visualización","value":290.90000000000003,"unit":"m","source":"Geometría releída del IFC; datum absoluto de proceso provisional","status":"derivado"}],"notes":["Las extensiones de la malla se miden en los ejes del proyecto tras el giro de implantación; no sustituyen las dimensiones locales del fabricante.","La envolvente, su volumen y los espesores de visualización no son volúmenes de material ni cantidades de compra, construcción o fabricación.","Las dimensiones documentadas distinguen cotas explícitas y medidas extraídas de contornos CAD; las dimensiones geométricas describen únicamente la malla publicada."]} | {"Estado de la planta":"Derivado del CAD y del giro de implantación","Nivel relativo del apoyo (m)":1.5,"Estado del nivel relativo":"Documentado en el plano de cimentaciones","Cero absoluto de visualización (m)":286.1,"Estado del cero absoluto":"Provisional","Cota del apoyo de visualización (m)":287.6,"Desplazamiento aplicado a la malla (m)":1.5000000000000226,"Criterio":"Nivel de apoyo relativo documentado. Se adopta el cero de proceso a 286,10 m solo para visualización; la equivalencia absoluta no está confirmada. No se añade un espesor de montaje sin cota del fabricante."} | ["Cara superior de vigas VC1 y plataforma en +1,500; diez pilares KZ1. El fondo del contenedor debe quedar sobre esa cara, no sobre la losa enterrada a 0,000.","El cero absoluto de la revisión no está definido; 286,10 m sigue siendo una hipótesis de coordinación.","Se alinea el punto inferior del conjunto del equipo, incluidos los pies ya representados, con la superficie de apoyo terminada; no se añade un espesor de calzos, placa o grout del fabricante no documentado."] | {"boundingBoxM":{"min":[39.557888,75.04734,2.6],"max":[43.694474,83.926273,5.9]},"extentsM":[4.136586,8.878933,3.3],"meshSurfaceM2":127.530001,"meshVolumeM3":84.645001,"closedSolid":true,"basis":"Magnitudes de las mallas representadas, no cantidades certificadas de obra, compra o fabricación. Las partes pueden compartir superficies; no se suman como un despiece de materiales."} | {"documentId":"LHD2609-JG00100-20260904","title":"Cimentaciones y pedestales de equipos · revisión recibida 04/09/2026","date":"2026-09-04","sheet":"13 / 13-13","sourceHandles":["1DE6F","1DC50"]} | {"elementId":"LV-CONTAINER","ifcGuid":"2L2nGL0FPQ3OpeSs_SxRqp","ifcClass":"IfcBuildingElementProxy","buildingId":"process_plant","buildingName":"Planta de proceso","sourceDocumentId":"EQ-CARGAS-20260825","sourceRepresentationKind":"equipment"} | 13 | 507 | 2629 | Altura del equipo: 3.3m | 15700 | 3 | 8.55 | 1.5 | JH_Trazabilidad - Observaciones: Referencia 13 del plano de cargas. El rectángulo identifica el contorno superior del equipo, no la cimentación perimetral.
Módulo de distribución eléctrica de alta tensión HV-CONTAINER | HV-CONTAINER | 9.62194 | 4.23874 | 3.3 | 287.6 | 290.9 | 136.98 | 92.07 | ["found_0904_f0afc95ba236c4","found_0904_3b311ea246324b","found_0904_d47b7eba926e93","found_0904_41f2fa27380188","found_0904_5fb13cd93ff0a2","found_0904_2a52ebeeeeddd3","found_0904_d1201ff518db4f","found_0904_075ddcfd9c66be","found_0904_b5531b2caa3049","found_0904_d5c6b9e968cd60","found_0904_aa2586cb630803","found_0904_5732c355da4910","found_0904_b2e389c2d6a507","found_0904_f8c6d0e535ad5c","found_0904_ed5f59783c550d"] | Apoyo relativo +1.500 m; cero absoluto provisional | {"documented":[{"label":"Dimensión X local del contorno CAD","value":9.3,"unit":"m","source":"EQ-CARGAS-20260825 · contorno CAD · handles 509","status":"derivado"},{"label":"Dimensión Y local del contorno CAD","value":3.0,"unit":"m","source":"EQ-CARGAS-20260825 · contorno CAD · handles 509","status":"derivado"},{"label":"Altura acotada","value":3.3,"unit":"m","source":"EQ-CARGAS-20260825 · handle 50D","status":"documentado"},{"label":"Cota relativa de la superficie de apoyo","value":1.5,"unit":"m","source":"LHD2609-JG00100-20260904 · sección 14 / 14-14 · 1E59F","status":"documentado"}],"geometry":[{"label":"Extensión de la malla en X","value":9.621943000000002,"unit":"m","source":"Geometría releída del IFC; datum absoluto de proceso provisional","status":"derivado"},{"label":"Extensión de la malla en Y","value":4.238738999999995,"unit":"m","source":"Geometría releída del IFC; datum absoluto de proceso provisional","status":"derivado"},{"label":"Extensión de la malla en Z","value":3.3000000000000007,"unit":"m","source":"Geometría releída del IFC; datum absoluto de proceso provisional","status":"derivado"},{"label":"Cota inferior de visualización","value":287.6,"unit":"m","source":"Geometría releída del IFC; datum absoluto de proceso provisional","status":"derivado"},{"label":"Cota superior de visualización","value":290.90000000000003,"unit":"m","source":"Geometría releída del IFC; datum absoluto de proceso provisional","status":"derivado"}],"notes":["Las extensiones de la malla se miden en los ejes del proyecto tras el giro de implantación; no sustituyen las dimensiones locales del fabricante.","La envolvente, su volumen y los espesores de visualización no son volúmenes de material ni cantidades de compra, construcción o fabricación.","Las dimensiones documentadas distinguen cotas explícitas y medidas extraídas de contornos CAD; las dimensiones geométricas describen únicamente la malla publicada."]} | {"Estado de la planta":"Derivado del CAD y del giro de implantación","Nivel relativo del apoyo (m)":1.5,"Estado del nivel relativo":"Documentado en el plano de cimentaciones","Cero absoluto de visualización (m)":286.1,"Estado del cero absoluto":"Provisional","Cota del apoyo de visualización (m)":287.6,"Desplazamiento aplicado a la malla (m)":1.5000000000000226,"Criterio":"Nivel de apoyo relativo documentado. Se adopta el cero de proceso a 286,10 m solo para visualización; la equivalencia absoluta no está confirmada. No se añade un espesor de montaje sin cota del fabricante."} | ["Contenedor de condensadores y variadores 10 kV. La asociación a HV-CONTAINER se apoya en la longitud de fabricante 9,300 m frente al módulo estructural de 9,250 m; verificar con las posiciones finales.","El cero absoluto de la revisión no está definido; 286,10 m sigue siendo una hipótesis de coordinación.","Se alinea el punto inferior del conjunto del equipo, incluidos los pies ya representados, con la superficie de apoyo terminada; no se añade un espesor de calzos, placa o grout del fabricante no documentado."] | {"boundingBoxM":{"min":[55.152125,79.338244,2.6],"max":[64.774068,83.576983,5.9]},"extentsM":[9.621943,4.238739,3.3],"meshSurfaceM2":136.979998,"meshVolumeM3":92.069998,"closedSolid":true,"basis":"Magnitudes de las mallas representadas, no cantidades certificadas de obra, compra o fabricación. Las partes pueden compartir superficies; no se suman como un despiece de materiales."} | {"documentId":"LHD2609-JG00100-20260904","title":"Cimentaciones y pedestales de equipos · revisión recibida 04/09/2026","date":"2026-09-04","sheet":"14 / 14-14","sourceHandles":["1E59F"]} | {"elementId":"HV-CONTAINER","ifcGuid":"0tJuNaqwvNjx$VAfFmSRv5","ifcClass":"IfcBuildingElementProxy","buildingId":"process_plant","buildingName":"Planta de proceso","sourceDocumentId":"EQ-CARGAS-20260825","sourceRepresentationKind":"equipment"} | 14 | 509 | 50D | Altura del equipo: 3.3m | 15300 | 9.3 | 3 | 1.5
Módulo de distribución eléctrica de 10 kV MV-CONTAINER | MV-CONTAINER | 7.14524 | 3.89823 | 3.3 | 287.6 | 290.9 | 105.48 | 67.32 | ["found_0904_5437d20ca4a5e2","found_0904_5fd42e9cd85676","found_0904_bb4b2f457d76a6","found_0904_e71532bfce3483","found_0904_8421c28e52c7e3","found_0904_ea9ba8ece9deba","found_0904_499ff58d04697b","found_0904_62918767cf4ba3","found_0904_ee7d9428005826","found_0904_40371ce5cfe23e","found_0904_0c93b645a183af"] | Apoyo relativo +1.500 m; cero absoluto provisional | {"documented":[{"label":"Dimensión X local del contorno CAD","value":6.8,"unit":"m","source":"EQ-CARGAS-20260825 · contorno CAD · handles 50F","status":"derivado"},{"label":"Dimensión Y local del contorno CAD","value":3.0,"unit":"m","source":"EQ-CARGAS-20260825 · contorno CAD · handles 50F","status":"derivado"},{"label":"Altura acotada","value":3.3,"unit":"m","source":"EQ-CARGAS-20260825 · handle 2616","status":"documentado"},{"label":"Cota relativa de la superficie de apoyo","value":1.5,"unit":"m","source":"LHD2609-JG00100-20260904 · sección 16 / 16-16 · 1E5A2","status":"documentado"}],"geometry":[{"label":"Extensión de la malla en X","value":7.145240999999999,"unit":"m","source":"Geometría releída del IFC; datum absoluto de proceso provisional","status":"derivado"},{"label":"Extensión de la malla en Y","value":3.898229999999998,"unit":"m","source":"Geometría releída del IFC; datum absoluto de proceso provisional","status":"derivado"},{"label":"Extensión de la malla en Z","value":3.3000000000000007,"unit":"m","source":"Geometría releída del IFC; datum absoluto de proceso provisional","status":"derivado"},{"label":"Cota inferior de visualización","value":287.6,"unit":"m","source":"Geometría releída del IFC; datum absoluto de proceso provisional","status":"derivado"},{"label":"Cota superior de visualización","value":290.90000000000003,"unit":"m","source":"Geometría releída del IFC; datum absoluto de proceso provisional","status":"derivado"}],"notes":["Las extensiones de la malla se miden en los ejes del proyecto tras el giro de implantación; no sustituyen las dimensiones locales del fabricante.","La envolvente, su volumen y los espesores de visualización no son volúmenes de material ni cantidades de compra, construcción o fabricación.","Las dimensiones documentadas distinguen cotas explícitas y medidas extraídas de contornos CAD; las dimensiones geométricas describen únicamente la malla publicada."]} | {"Estado de la planta":"Derivado del CAD y del giro de implantación","Nivel relativo del apoyo (m)":1.5,"Estado del nivel relativo":"Documentado en el plano de cimentaciones","Cero absoluto de visualización (m)":286.1,"Estado del cero absoluto":"Provisional","Cota del apoyo de visualización (m)":287.6,"Desplazamiento aplicado a la malla (m)":1.5000000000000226,"Criterio":"Nivel de apoyo relativo documentado. Se adopta el cero de proceso a 286,10 m solo para visualización; la equivalencia absoluta no está confirmada. No se añade un espesor de montaje sin cota del fabricante."} | ["Contenedor de 10 kV, seis pilares KZ1. La asociación a MV-CONTAINER se apoya en la longitud de fabricante 6,800 m frente al módulo estructural de 6,750 m; verificar con las posiciones finales.","El título chino del plano de cimentación repite incorrectamente condensadores y variadores, mientras título español y planta elevada dicen contenedor de 10 kV.","El cero absoluto de la revisión no está definido; 286,10 m sigue siendo una hipótesis de coordinación.","Se alinea el punto inferior del conjunto del equipo, incluidos los pies ya representados, con la superficie de apoyo terminada; no se añade un espesor de calzos, placa o grout del fabricante no documentado."] | {"boundingBoxM":{"min":[47.128074,80.781705,2.6],"max":[54.273315,84.679935,5.9]},"extentsM":[7.145241,3.89823,3.3],"meshSurfaceM2":105.480004,"meshVolumeM3":67.320007,"closedSolid":true,"basis":"Magnitudes de las mallas representadas, no cantidades certificadas de obra, compra o fabricación. Las partes pueden compartir superficies; no se suman como un despiece de materiales."} | {"documentId":"LHD2609-JG00100-20260904","title":"Cimentaciones y pedestales de equipos · revisión recibida 04/09/2026","date":"2026-09-04","sheet":"16 / 16-16","sourceHandles":["1E5A2"]} | {"elementId":"MV-CONTAINER","ifcGuid":"0jhCB4Gt5JqekSYr$ZYL59","ifcClass":"IfcBuildingElementProxy","buildingId":"process_plant","buildingName":"Planta de proceso","sourceDocumentId":"EQ-CARGAS-20260825","sourceRepresentationKind":"equipment"} | 16 | 50F | 2616 | Altura del equipo: 3.3m | 12000 | 6.8 | 3 | 1.5
Módulo de instrumentación y control IC-CONTAINER | IC-CONTAINER | 4.27774 | 10.2591 | 3 | 287.6 | 290.6 | 136.105 | 88.0575 | ["found_0904_a8a3fbca2a122b","found_0904_b71752b17c94a5","found_0904_29a4127fe30ab6","found_0904_ddeb8c03984179","found_0904_45dfd7825aea35","found_0904_22501c5a816ffd","found_0904_6a94c9fa32a560","found_0904_9722ff0b284716","found_0904_da05fb84c57029","found_0904_cf7cdc7477904e","found_0904_46423874b3d85e","found_0904_aeb5610b3d5f11","found_0904_57c4e0ee32d3f7","found_0904_a62b23424415b1","found_0904_ea78e8246d70ca"] | Apoyo relativo +1.500 m; cero absoluto provisional | {"documented":[{"label":"Dimensión X local del contorno CAD","value":2.95,"unit":"m","source":"EQ-CARGAS-20260825 · contorno CAD · handles 500","status":"derivado"},{"label":"Dimensión Y local del contorno CAD","value":9.95,"unit":"m","source":"EQ-CARGAS-20260825 · contorno CAD · handles 500","status":"derivado"},{"label":"Altura acotada","value":3.0,"unit":"m","source":"EQ-CARGAS-20260825 · handle 263B","status":"documentado"},{"label":"Cota relativa de la superficie de apoyo","value":1.5,"unit":"m","source":"LHD2609-JG00100-20260904 · sección 15 / 15-15 · 1E615","status":"documentado"}],"geometry":[{"label":"Extensión de la malla en X","value":4.277737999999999,"unit":"m","source":"Geometría releída del IFC; datum absoluto de proceso provisional","status":"derivado"},{"label":"Extensión de la malla en Y","value":10.259075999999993,"unit":"m","source":"Geometría releída del IFC; datum absoluto de proceso provisional","status":"derivado"},{"label":"Extensión de la malla en Z","value":3.0,"unit":"m","source":"Geometría releída del IFC; datum absoluto de proceso provisional","status":"derivado"},{"label":"Cota inferior de visualización","value":287.6,"unit":"m","source":"Geometría releída del IFC; datum absoluto de proceso provisional","status":"derivado"},{"label":"Cota superior de visualización","value":290.6,"unit":"m","source":"Geometría releída del IFC; datum absoluto de proceso provisional","status":"derivado"}],"notes":["Las extensiones de la malla se miden en los ejes del proyecto tras el giro de implantación; no sustituyen las dimensiones locales del fabricante.","La envolvente, su volumen y los espesores de visualización no son volúmenes de material ni cantidades de compra, construcción o fabricación.","Las dimensiones documentadas distinguen cotas explícitas y medidas extraídas de contornos CAD; las dimensiones geométricas describen únicamente la malla publicada."]} | {"Estado de la planta":"Derivado del CAD y del giro de implantación","Nivel relativo del apoyo (m)":1.5,"Estado del nivel relativo":"Documentado en el plano de cimentaciones","Cero absoluto de visualización (m)":286.1,"Estado del cero absoluto":"Provisional","Cota del apoyo de visualización (m)":287.6,"Desplazamiento aplicado a la malla (m)":1.5000000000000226,"Criterio":"Nivel de apoyo relativo documentado. Se adopta el cero de proceso a 286,10 m solo para visualización; la equivalencia absoluta no está confirmada. No se añade un espesor de montaje sin cota del fabricante."} | ["Cara superior de vigas VC1 y plataforma en +1,500; diez pilares KZ1.","El cero absoluto de la revisión no está definido; 286,10 m sigue siendo una hipótesis de coordinación.","Se alinea el punto inferior del conjunto del equipo, incluidos los pies ya representados, con la superficie de apoyo terminada; no se añade un espesor de calzos, placa o grout del fabricante no documentado."] | {"boundingBoxM":{"min":[37.911778,62.915232,2.6],"max":[42.189516,73.174308,5.6]},"extentsM":[4.277738,10.259076,3.0],"meshSurfaceM2":136.105018,"meshVolumeM3":88.057519,"closedSolid":true,"basis":"Magnitudes de las mallas representadas, no cantidades certificadas de obra, compra o fabricación. Las partes pueden compartir superficies; no se suman como un despiece de materiales."} | {"documentId":"LHD2609-JG00100-20260904","title":"Cimentaciones y pedestales de equipos · revisión recibida 04/09/2026","date":"2026-09-04","sheet":"15 / 15-15","sourceHandles":["1E615"]} | {"elementId":"IC-CONTAINER","ifcGuid":"2U8KMZjLrQxurp0z_$oFiT","ifcClass":"IfcBuildingElementProxy","buildingId":"process_plant","buildingName":"Planta de proceso","sourceDocumentId":"EQ-CARGAS-20260825","sourceRepresentationKind":"equipment"} | 15 | 500 | 263B | Altura del equipo: 3m | 6000 | 2.95 | 9.95 | 1.5
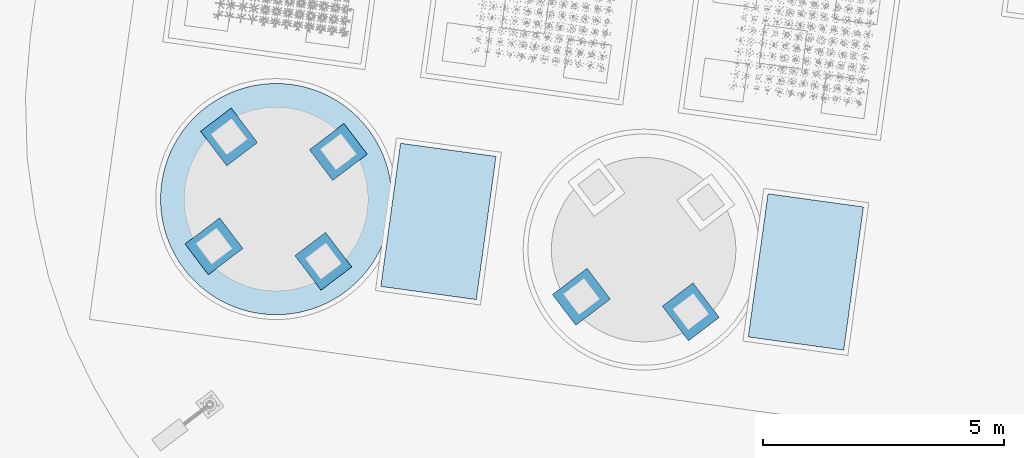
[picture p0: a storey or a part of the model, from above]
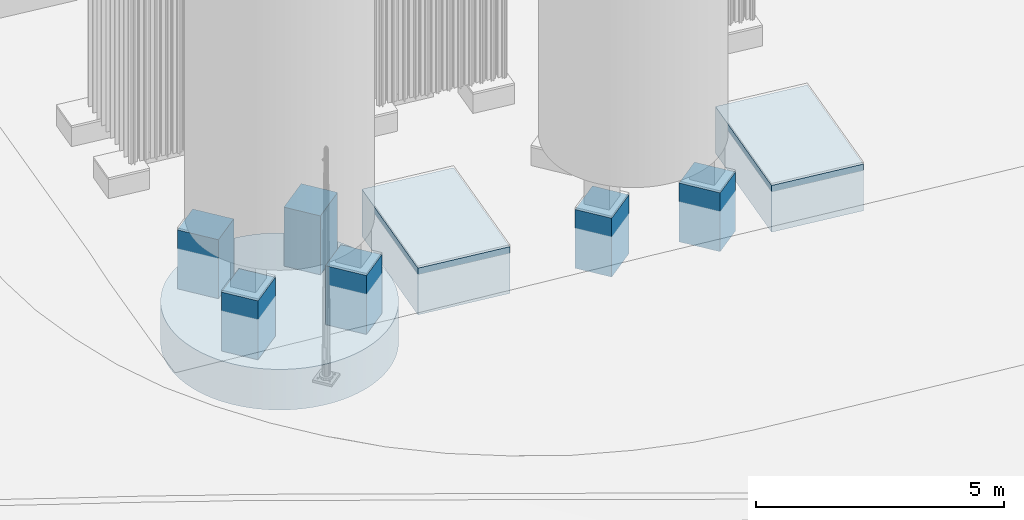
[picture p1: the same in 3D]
Properties of the parts of a building model (IFC4), part 54 of 134

# IfcBuildingElementProxy: Envolvente de equipo (5)
Name | Reference = Identificador del fabricante o del modelo = Identificador del objeto = Identificador | Extensión de la malla en X (m) = ExtensionX (m) | Extensión de la malla en Y (m) = ExtensionY (m) | Extensión de la malla en Z (m) = ExtensionZ (m) = Altura (m) = Altura acotada (m) | Cota inferior de visualización (m) | Cota superior de visualización (m) | SuperficieDeLaMalla (m2) | VolumenGeometrico (m3) | ElementosDeCimentacion = foundationIds | level | dimensions | positioning = PosicionYEstado | issues = IncidenciasPendientes | geometryMetrics | installationSource = Fuente del nivel de apoyo | visualizationIdentity | Referencia en el plano del fabricante | Identificadores CAD del contorno (handles) | Identificador CAD de la cota de altura (handle) | Cota de altura del fabricante (traducción) | Masa propia indicada (kg) | Dimensión X local (m) = Dimensión X local del contorno CAD (m) | Dimensión Y local (m) = Dimensión Y local del contorno CAD (m) | Nivel relativo de apoyo documentado (m) = Cota relativa de la superficie de apoyo (m)
Caseta de analizadores ANALYSIS-CABIN | ANALYSIS-CABIN | 2.81721 | 2.81721 | 2.8 | 286.3 | 289.1 | 40.5 | 17.5 | ["found_0904_a9c892c36ff3b0","found_0904_2945d17712b119","found_0904_5fe3eabcbe4201","found_0904_c330c932b1c30a","found_0904_a18f40c00197ec","found_0904_181c1ed7abf435"] | Apoyo relativo +0.200 m; cero absoluto provisional | {"documented":[{"label":"Dimensión X local del contorno CAD","value":2.5,"unit":"m","source":"EQ-CARGAS-20260825 · contorno CAD · handles 534","status":"derivado"},{"label":"Dimensión Y local del contorno CAD","value":2.5,"unit":"m","source":"EQ-CARGAS-20260825 · contorno CAD · handles 534","status":"derivado"},{"label":"Altura acotada","value":2.8,"unit":"m","source":"EQ-CARGAS-20260825 · handle 538","status":"documentado"},{"label":"Cota relativa de la superficie de apoyo","value":0.2,"unit":"m","source":"LHD2609-JG00100-20260904 · sección 20 / 20-20 · 2487F, 248A7","status":"documentado"}],"geometry":[{"label":"Extensión de la malla en X","value":2.817211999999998,"unit":"m","source":"Geometría releída del IFC; datum absoluto de proceso provisional","status":"derivado"},{"label":"Extensión de la malla en Y","value":2.8172110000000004,"unit":"m","source":"Geometría releída del IFC; datum absoluto de proceso provisional","status":"derivado"},{"label":"Extensión de la malla en Z","value":2.8,"unit":"m","source":"Geometría releída del IFC; datum absoluto de proceso provisional","status":"derivado"},{"label":"Cota inferior de visualización","value":286.3,"unit":"m","source":"Geometría releída del IFC; datum absoluto de proceso provisional","status":"derivado"},{"label":"Cota superior de visualización","value":289.1,"unit":"m","source":"Geometría releída del IFC; datum absoluto de proceso provisional","status":"derivado"}],"notes":["Las extensiones de la malla se miden en los ejes del proyecto tras el giro de implantación; no sustituyen las dimensiones locales del fabricante.","La envolvente, su volumen y los espesores de visualización no son volúmenes de material ni cantidades de compra, construcción o fabricación.","Las dimensiones documentadas distinguen cotas explícitas y medidas extraídas de contornos CAD; las dimensiones geométricas describen únicamente la malla publicada."]} | {"Estado de la planta":"Derivado del CAD y del giro de implantación","Nivel relativo del apoyo (m)":0.2,"Estado del nivel relativo":"Documentado en el plano de cimentaciones","Cero absoluto de visualización (m)":286.1,"Estado del cero absoluto":"Provisional","Cota del apoyo de visualización (m)":286.3,"Desplazamiento aplicado a la malla (m)":0.2000000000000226,"Criterio":"Nivel de apoyo relativo documentado. Se adopta el cero de proceso a 286,10 m solo para visualización; la equivalencia absoluta no está confirmada. No se añade un espesor de montaje sin cota del fabricante."} | ["DL + LL = 7 700 kg en el plano; masa propia y carga variable sin desglose.","La placa empotrada MJ3 termina al ras de la cara +0,200 según sección; no se presupone espesor adicional de montaje.","El cero absoluto de la revisión no está definido; 286,10 m sigue siendo una hipótesis de coordinación.","Se alinea el punto inferior del conjunto del equipo, incluidos los pies ya representados, con la superficie de apoyo terminada; no se añade un espesor de calzos, placa o grout del fabricante no documentado."] | {"boundingBoxM":{"min":[44.160521,39.229115,1.3],"max":[46.977733,42.046326,4.1]},"extentsM":[2.817212,2.817211,2.8],"meshSurfaceM2":40.499998,"meshVolumeM3":17.499999,"closedSolid":true,"basis":"Magnitudes de las mallas representadas, no cantidades certificadas de obra, compra o fabricación. Las partes pueden compartir superficies; no se suman como un despiece de materiales."} | {"documentId":"LHD2609-JG00100-20260904","title":"Cimentaciones y pedestales de equipos · revisión recibida 04/09/2026","date":"2026-09-04","sheet":"20 / 20-20","sourceHandles":["2487F","248A7"]} | {"elementId":"ANALYSIS-CABIN","ifcGuid":"34Qv6xzVzHseI4tNzTK8V2","ifcClass":"IfcBuildingElementProxy","buildingId":"process_plant","buildingName":"Planta de proceso","sourceDocumentId":"EQ-CARGAS-20260825","sourceRepresentationKind":"equipment"} | 20 | 534 | 538 | Altura del equipo: 2.8m | Sin desglose | 2.5 | 2.5 | 0.2 | JH_Trazabilidad - Observaciones: El plano indica carga permanente más variable, DL + LL = 7 700 kg; no desglosa la masa propia.; Carga permanente más variable indicada (kg): 7700

# IfcBuildingElementProxy: Lindero de parcela, Lindero de parcela · línea de control de coordenadas
In: Parcela industrial Jinhong
Description: Lindero de parcela; PredefinedType: USERDEFINED; Document: Planos de urbanización y ordenación general de Jinhong; Planos de urbanización y ordenación general de Jinhong; Group: Urbanización; BIM · Referencias documentales
JH_DimensionesDelModelo - Extensión de la malla en X: 143.1 m; Extensión de la malla en Y: 106.763 m; Extensión de la malla en Z: 2.73 m; Cota inferior del modelo: 285.41 m; Cota superior del modelo: 288.14 m
Pset_BuildingElementProxyCommon - Reference: site_006
JH_MagnitudesGeometricas - ExtensionX: 143.1 m; ExtensionY: 106.763 m; ExtensionZ: 2.73 m; SuperficieDeLaMalla: 300.461 m2; VolumenGeometrico: 3.08661 m3
JH_InformacionBIM - buildingId: site; buildingName: Urbanización y parcela; level: Exterior · control en planta; category: Lindero de parcela; ifcClass: IfcBuildingElementProxy; material: {"name":"No especificado","source":"Sin especificación de material en la documentación revisada","status":"unknown"}; dimensions: {"documented":[{"label":"Coordenadas explícitas del lindero","value":7,"unit":"puntos","source":"URB-20260731 · U003","status":"documentado"}],"geometry":[{"label":"Extensión de la malla en X","value":143.099973,"unit":"m","source":"Calculada a partir de los vértices del modelo","status":"derivado"},{"label":"Extensión de la malla en Y","value":106.762943,"unit":"m","source":"Calculada a partir de los vértices del modelo","status":"derivado"},{"label":"Extensión de la malla en Z","value":2.73,"unit":"m","source":"Calculada a partir de los vértices del modelo","status":"derivado"},{"label":"Cota inferior del modelo","value":285.41,"unit":"m","source":"Coordenada Z mínima de la malla más origen vertical de 285 m","status":"derivado"},{"label":"Cota superior del modelo","value":288.14,"unit":"m","source":"Coordenada Z máxima de la malla más origen vertical de 285 m","status":"derivado"}],"notes":["Las extensiones de la malla se miden en los ejes del proyecto tras el giro de implantación; no sustituyen las dimensiones locales del fabricante.","La envolvente, su volumen y los espesores de visualización no son volúmenes de material ni cantidades de compra, construcción o fabricación.","Las dimensiones documentadas distinguen cotas explícitas y medidas extraídas de contornos CAD; las dimensiones geométricas describen únicamente la malla publicada."]}; source: {"documentId":"URB-20260731","title":"Planos de urbanización y ordenación general de Jinhong","sheet":"U003 · página 4","date":"2026-07-31"}; status: derivado; positioning: {"horizontalStatus":"derivado","verticalStatus":"provisional","baseElevationM":285.41,"note":"Cota de representación derivada del modelo; superficie real de apoyo pendiente de coordinación."}; issues: ["Arco suroeste sustituido provisionalmente por una cuerda. La banda visual no representa un muro ni su sección. No acredita un deslinde legal."]; geometryMetrics: {"boundingBoxM":{"min":[-5.818999,2.629027,0.41],"max":[137.280974,109.39197,3.14]},"extentsM":[143.099973,106.762943,2.73],"meshSurfaceM2":300.460913,"meshVolumeM3":3.086612,"closedSolid":true,"basis":"Geometría triangulada releída del IFC; envolventes y magnitudes no contractuales."}; ifcAssociations: {"material":false,"document":true,"quantities":true,"containerGuid":"17utmjd_LKsAVvPyuSUhFt","containerName":"Parcela industrial Jinhong"}; visualLayer: {"id":"references","name":"Referencias documentales"}; materialAppearance: {"profileId":"survey_reference","name":"Referencia documental · ámbar","materialName":"No especificado","physicalMaterialStatus":"unknown","physicalMaterialSource":"Sin especificación de material en la documentación revisada","appearanceStatus":"referencia","appearanceBasis":"Interpretación visual del material documental; el acabado, tono y parámetros PBR no son una especificación contractual.","note":"La apariencia gráfica no modifica ni confirma la especificación física del material."}; componentSeparation: {"status":"objeto_independiente","note":"Control de visibilidad del objeto completo; la clasificación no altera la malla."}; visualizationIdentity: {"elementId":"site_006","ifcGuid":"2NWv9tIerLXOjmsgOAlMOf","ifcClass":"IfcBuildingElementProxy","buildingId":"site","buildingName":"Urbanización y parcela","sourceDocumentId":"URB-20260731","sourceRepresentationKind":"documentary_mesh"}; classification: {"layerId":"references","layerName":"Referencias documentales","role":"Lindero de parcela","basis":"Clasificación por función del elemento; no modifica las especificaciones documentales."}; layerId: references; appearance: {"profileId":"survey_reference","name":"Referencia documental · ámbar","status":"referencia","basis":"Interpretación visual del material documental; el acabado, tono y parámetros PBR no son una especificación contractual.","physicalMaterialUnchanged":true}
JH_Trazabilidad - Documento de origen: Planos de urbanización y ordenación general de Jinhong · 2026-07-31 · U003 · página 4; Lámina de origen: U003 · página 4 del PDF; Estado de la geometría: Trazado a partir de siete coordenadas explícitas del lindero; el arco suroeste se sustituye provisionalmente por su cuerda.; Naturaleza de la representación: Banda estrecha de visualización del lindero; no representa un cerramiento físico ni una anchura de medición.; Identificador del objeto: site_006; Disciplina: Urbanización; Clase IFC: IfcBuildingElementProxy; Fase del modelo: V0.1 · Reconstrucción a partir de planos y coordinación preliminar; Representación geométrica IFC: Sólido IFC4 mediante malla triangular cerrada; Aplicabilidad a mediciones: Los equipos se representan mediante envolventes. Los espesores y alturas supuestos y el volumen de las envolventes no representan cantidades de materiales, compras, construcción o fabricación.; Material: No especificado; Estado de la información: derivado; Capa BIM: Referencias documentales; Acabado de visualización: Referencia documental · ámbar; Estado del acabado: referencia; Identificador: site_006; Categoria: Lindero de parcela; ClaseIFC: IfcBuildingElementProxy; EstadoDeInformacion: derivado; DocumentoFuente: {"documentId":"URB-20260731","title":"Planos de urbanización y ordenación general de Jinhong","sheet":"U003 · página 4","date":"2026-07-31"}; IncidenciasPendientes: ["Arco suroeste sustituido provisionalmente por una cuerda. La banda visual no representa un muro ni su sección. No acredita un deslinde legal."]; UsoDeLasMagnitudes: Geometría de coordinación. Los volúmenes de referencia y subcomponentes no son cantidades de material ni componentes de fabricación certificados.
JH_CriterioDePosicion - PosicionYEstado: {"horizontalStatus":"derivado","verticalStatus":"provisional","baseElevationM":285.41,"note":"Cota de representación derivada del modelo; superficie real de apoyo pendiente de coordinación."}
JH_EvidenciaDeMaterial - name: No especificado; source: Sin especificación de material en la documentación revisada; status: unknown
JH_DimensionesDocumentadas - Coordenadas explícitas del lindero: 7
JH_CapaBIM - IdentificadorCapa: references; NombreCapa: Referencias documentales; Funcion: Lindero de parcela; VisibilidadInicial: no
JH_AcabadoVisual - Perfil: survey_reference; Acabado: Referencia documental · ámbar; ColorRGB: [0.784314,0.584314,0.282353]; Rugosidad: 1; Metallicidad: 0; Estado: referencia; Referencia: Interpretación visual del material documental; el acabado, tono y parámetros PBR no son una especificación contractual.; Nota: La apariencia no certifica el material físico ni el acabado de fabricación.

# IfcBuildingElementProxy: Marcador de equipo en planta (6)
In: Parcela industrial Jinhong
PredefinedType: USERDEFINED
JH_CoordinacionCimentaciones - Relacion: Correspondencia documental; no verifica anclajes ni cotas de montaje.
JH_AcabadoVisual - Nota: La apariencia no certifica el material físico ni el acabado de fabricación.
JH_InformacionBIM - buildingId: process_plant; buildingName: Planta de proceso; ifcClass: IfcBuildingElementProxy; status: provisional; isReferenceOnly: yes; componentSeparation: {"status":"objeto_independiente","note":"Control de visibilidad del objeto completo; la clasificación no altera la malla."}
JH_Trazabilidad - Disciplina: Equipos; Clase IFC: IfcBuildingElementProxy; Fase del modelo: Revisión de la zona de separación de aire · septiembre de 2026; Material: No especificado; Criterio de instalación: Nivel de apoyo relativo documentado. Se adopta el cero de proceso a 286,10 m solo para visualización; la equivalencia absoluta no está confirmada. No se añade un espesor de montaje sin cota del fabricante.; ClaseIFC: IfcBuildingElementProxy; EstadoDeInformacion: provisional
JH_EvidenciaDeMaterial - name: No especificado; status: unknown
Name | Description = Funcion = category = Categoria | Document | Reference = Identificador del objeto = Identificador | Extensión de la malla en X (m) = ExtensionX (m) | Extensión de la malla en Y (m) = ExtensionY (m) | Extensión de la malla en Z (m) = ExtensionZ (m) | Cota inferior de visualización (m) | Cota superior de visualización (m) | SuperficieDeLaMalla (m2) | VolumenGeometrico (m3) | ElementosDeCimentacion = foundationIds | IdentificadorCapa = layerId | NombreCapa = Capa BIM | VisibilidadInicial | Perfil | Acabado = Acabado de visualización | ColorRGB | Rugosidad | Metallicidad | Estado = Estado del acabado | Referencia | level | material | dimensions | JH_InformacionBIM, source = DocumentoFuente | positioning = PosicionYEstado | issues = IncidenciasPendientes | geometryMetrics | ifcAssociations | installationSource = Fuente del nivel de apoyo | representationKind | JH_InformacionBIM, heightStatus | heightReference | visualLayer | materialAppearance | visualizationIdentity | classification | appearance | Referencia en el plano del fabricante | Grado de definición | Hipótesis de modelado = Estado de la cota de instalación | Documento de origen | Identificadores CAD del contorno (handles) | Origen de las dimensiones | Dimensiones de la plataforma de equipos (m) | Implantación de la plataforma de equipos | Convención de coordenadas | Representación geométrica IFC | Aplicabilidad a mediciones | Estado de la información | Nivel relativo de apoyo documentado (m) = Cota relativa de la superficie de apoyo (m) | Estado de altura | UsoDeLasMagnitudes | JH_EvidenciaDeMaterial, source | Group
Caja fría del intercambiador principal · solo ámbito en planta; altura desconocida | Equipo pendiente de altura; plano fuente conservado | Plano del fabricante: implantación de equipos · referencia E7; Cimentaciones de equipos y pedestales del fabricante · revisión recibida 04/09/2026; Soportes de equipos SL1201 y SL401/402; Planta de estructuras metálicas; Plantas generales de instrumentación; Alumbrado de la caja fría | CB-HX-PLAN | 4.04645 | 4.04564 | 0.1 | 286.2 | 286.3 | 27.2191 | 1.28915 | ["found_0904_f7e6bebab60859","found_0904_ab1632a7d9dd78","found_0904_e82a8a5ec7336e","found_0904_323dc0fbe26a0b","found_0904_3aab66a70a9bd0","found_0904_33c531229e93fa"] | references | Referencias documentales | no | survey_reference | Referencia documental · ámbar | [0.784314,0.584314,0.282353] | 1 | 0 | referencia | Interpretación visual del material documental; el acabado, tono y parámetros PBR no son una especificación contractual. | Apoyo relativo +0.100 m; cero absoluto provisional | {"name":"No especificado","source":"Sin especificación de material en la documentación revisada","status":"unknown"} | {"documented":[{"label":"Dimensión X local del contorno CAD","value":3.59094,"unit":"m","source":"EQ-IMPLANTACION-20260430 · contorno CAD · handles 91453,91471,91593,91599","status":"derivado"},{"label":"Dimensión Y local del contorno CAD","value":3.59,"unit":"m","source":"EQ-IMPLANTACION-20260430 · contorno CAD · handles 91453,91471,91593,91599","status":"derivado"},{"label":"Cota relativa de la superficie de apoyo","value":0.1,"unit":"m","source":"LHD2609-JG00100-20260904 · sección 4 / 4-4 / 4a-4a · 1FE9E, 1FF16, 1FF22","status":"documentado"}],"geometry":[{"label":"Extensión de la malla en X","value":4.046447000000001,"unit":"m","source":"Geometría releída del IFC; datum absoluto de proceso provisional","status":"derivado"},{"label":"Extensión de la malla en Y","value":4.045643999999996,"unit":"m","source":"Geometría releída del IFC; datum absoluto de proceso provisional","status":"derivado"},{"label":"Extensión de la malla en Z","value":0.09999999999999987,"unit":"m","source":"Geometría releída del IFC; datum absoluto de proceso provisional","status":"derivado"},{"label":"Cota inferior de visualización","value":286.20000000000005,"unit":"m","source":"Geometría releída del IFC; datum absoluto de proceso provisional","status":"derivado"},{"label":"Cota superior de visualización","value":286.3,"unit":"m","source":"Geometría releída del IFC; datum absoluto de proceso provisional","status":"derivado"}],"notes":["Las extensiones de la malla se miden en los ejes del proyecto tras el giro de implantación; no sustituyen las dimensiones locales del fabricante.","La envolvente, su volumen y los espesores de visualización no son volúmenes de material ni cantidades de compra, construcción o fabricación.","Las dimensiones documentadas distinguen cotas explícitas y medidas extraídas de contornos CAD; las dimensiones geométricas describen únicamente la malla publicada."]} | {"documentId":"EQ-IMPLANTACION-20260430","title":"Plano del fabricante: implantación de equipos · referencia E7","sheet":"Espacio modelo; referencia E7 en el nombre del archivo","date":"2026-04-30"} | {"Estado de la planta":"Derivado del CAD y del giro de implantación","Nivel relativo del apoyo (m)":0.1,"Estado del nivel relativo":"Documentado en el plano de cimentaciones","Cero absoluto de visualización (m)":286.1,"Estado del cero absoluto":"Provisional","Cota del apoyo de visualización (m)":286.20000000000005,"Desplazamiento aplicado a la malla (m)":0.10000000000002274,"Criterio":"Nivel de apoyo relativo documentado. Se adopta el cero de proceso a 286,10 m solo para visualización; la equivalencia absoluta no está confirmada. No se añade un espesor de montaje sin cota del fabricante."} | ["Marcador de 0,10 m de espesor: representa únicamente un ámbito en planta, no el cuerpo del equipo ni su altura física.","Cota de la plataforma elevada +0,100; losa exterior a 0,000. La relación XY de cada subcaja con la plataforma elevada debe verificarse en el modelo final.","Fondo ambiguo: sección 4-4 indica -1,000 pero cotas 1500 mm y sección 4a-4a indican -1,500.","El cero absoluto de la revisión no está definido; 286,10 m sigue siendo una hipótesis de coordinación.","Se alinea el punto inferior del conjunto del equipo, incluidos los pies ya representados, con la superficie de apoyo terminada; no se añade un espesor de calzos, placa o grout del fabricante no documentado.","GD05001, lámina 2: +3,800 m corresponde al techo de la caja de paso del expansor; +6,050 m al soporte SL401/402; +0,100 m al apoyo inferior. No equivalen a las alturas físicas de los expansores. Relación con cada envolvente del modelo pendiente de confirmar; se conservan los volúmenes provisionales.","DQ05000 H1 contiene cuatro alzados de alumbrado y LAMP1–15. El texto chino indica poste de 2,0 m y el inglés 2,5 m: discrepancia pendiente. Los alzados sin cotas no confirman la altura total del equipo ni los niveles de plataformas."] | {"boundingBoxM":{"min":[53.638494,42.274351,1.2],"max":[57.684941,46.319995,1.3]},"extentsM":[4.046447,4.045644,0.1],"meshSurfaceM2":27.219133,"meshVolumeM3":1.289147,"closedSolid":true,"basis":"Magnitudes de las mallas representadas, no cantidades certificadas de obra, compra o fabricación. Las partes pueden compartir superficies; no se suman como un despiece de materiales."} | {"material":false,"document":true,"quantities":true,"containerGuid":"17utmjd_LKsAVvPyuSUhFt","containerName":"Parcela industrial Jinhong"} | {"documentId":"LHD2609-JG00100-20260904","title":"Cimentaciones y pedestales de equipos · revisión recibida 04/09/2026","date":"2026-09-04","sheet":"4 / 4-4 / 4a-4a","sourceHandles":["1FE9E","1FF16","1FF22"]} | sourcePlanReference | unknown | {"valueM":null,"sourceSupported":false,"reason":"La altura propia de este módulo no figura en las fuentes revisadas. Los aproximadamente 30 m de la columna principal y las alturas de sus puntos de venteo no definen este módulo."} | {"id":"references","name":"Referencias documentales"} | {"profileId":"survey_reference","name":"Referencia documental · ámbar","materialName":"No especificado","physicalMaterialStatus":"unknown","physicalMaterialSource":"Sin especificación de material en la documentación revisada","appearanceStatus":"referencia","appearanceBasis":"Interpretación visual del material documental; el acabado, tono y parámetros PBR no son una especificación contractual.","note":"La apariencia gráfica no modifica ni confirma la especificación física del material."} | {"elementId":"CB-HX-PLAN","ifcGuid":"3gx9CHcbPTL8VqelH6iFkl","ifcClass":"IfcBuildingElementProxy","buildingId":"process_plant","buildingName":"Planta de proceso","sourceDocumentId":"EQ-IMPLANTACION-20260430","sourceRepresentationKind":"planReference"} | {"layerId":"references","layerName":"Referencias documentales","role":"Equipo pendiente de altura; plano fuente conservado","basis":"Clasificación por función del elemento; no modifica las especificaciones documentales."} | {"profileId":"survey_reference","name":"Referencia documental · ámbar","status":"referencia","basis":"Interpretación visual del material documental; el acabado, tono y parámetros PBR no son una especificación contractual.","physicalMaterialUnchanged":true} | 4 | Únicamente se identifica un ámbito en planta; altura física del equipo sin confirmar. | Nivel de apoyo relativo documentado. Se adopta el cero de proceso a 286,10 m solo para visualización; la equivalencia absoluta no está confirmada. No se añade un espesor de montaje sin cota del fabricante. | Plano del fabricante: implantación de equipos · referencia E7 · 2026-04-30 · Espacio modelo; referencia E7 en el nombre del archivo | 91453,91471,91593,91599 | Contorno del equipo representado con línea de doble trazo y punto dentro del bloque CAD activo del fabricante. El contorno grueso exterior corresponde a la cimentación y no se adopta como envolvente del equipo. | 27 × 57 m; dimensiones acotadas en el plano general. | El punto de referencia del fabricante coincide con la esquina suroeste de la zona de equipos. Giro local de −7,82824° para la implantación en coordenadas UTM. | Coordenadas locales del proyecto en metros. Añadir (729400, 4301550, 285) para recuperar las coordenadas UTM y las cotas del plano. | Sólido IFC4 mediante malla triangular cerrada | Los equipos se representan mediante envolventes. Los espesores y alturas supuestos y el volumen de las envolventes no representan cantidades de materiales, compras, construcción o fabricación. | provisional | 0.1 | Pendiente de plano del fabricante | Geometría de coordinación basada en planos recibidos; no sustituye el modelo de fabricación ni una medición certificada. Datum absoluto de proceso provisional. | Sin especificación de material en la documentación revisada | Equipos; Zona de separación de aire; BIM · Referencias documentales | JH_RevisionDocumental20260909 - Criterio: Documentación complementaria recibida el 09/09/2026. Tuberías: paquete actualizado el 07/08; fechas y revisiones por plano. La recepción no cambia la fecha de diseño. Se mantienen cargas del 25/08 y cimentaciones recibidas el 04/09 frente a las versiones anteriores incluidas.; Documentos: SOPC-PROCESS_020 | SOPC-PROCESS_019 | SOPC-INSTRUMENT_002; Conclusiones: GD05001, lámina 2: +3,800 m corresponde al techo de la caja de paso del expansor; +6,050 m al soporte SL401/402; +0,100 m al apoyo inferior. No equivalen a las alturas físicas de los expansores. Relación con cada envolvente del modelo pendiente de confirmar; se conservan los volúmenes provisionales.; GeometriaModificada: no; JH_InformacionBIM - supplementaryDrawingReview: {"fecha":"2026-09-09","estado":"Revisión documental; geometría conservada","criterio":"Documentación complementaria recibida el 09/09/2026. Tuberías: paquete actualizado el 07/08; fechas y revisiones por plano. La recepción no cambia la fecha de diseño. Se mantienen cargas del 25/08 y cimentaciones recibidas el 04/09 frente a las versiones anteriores incluidas.","documentos":["SOPC-PROCESS_020","SOPC-PROCESS_019","SOPC-INSTRUMENT_002","SOPC-ELECTRICAL_003"],"conclusiones":["GD05001, lámina 2: +3,800 m corresponde al techo de la caja de paso del expansor; +6,050 m al soporte SL401/402; +0,100 m al apoyo inferior. No equivalen a las alturas físicas de los expansores. Relación con cada envolvente del modelo pendiente de confirmar; se conservan los volúmenes provisionales.","DQ05000 H1 contiene cuatro alzados de alumbrado y LAMP1–15. El texto chino indica poste de 2,0 m y el inglés 2,5 m: discrepancia pendiente. Los alzados sin cotas no confirman la altura total del equipo ni los niveles de plataformas."]}; JH_Trazabilidad - Bloque CAD: 14257432; Identificador CAD de la inserción (handle): 9122B; Identificador CAD del rótulo (handle): 9159C; Origen de la altura: No se ha localizado una altura acotada del equipo.; Alcance de la geometría: Marcador del ámbito en planta; Dimensión X local del contorno (m): 3.59094; Dimensión Y local del contorno (m): 3.59; Capa: Equipos pendientes de altura; Revisión documental complementaria: {"fecha":"2026-09-09","estado":"Revisión documental; geometría conservada","criterio":"Documentación complementaria recibida el 09/09/2026. Tuberías: paquete actualizado el 07/08; fechas y revisiones por plano. La recepción no cambia la fecha de diseño. Se mantienen cargas del 25/08 y cimentaciones recibidas el 04/09 frente a las versiones anteriores incluidas.","documentos":["SOPC-PROCESS_020","SOPC-PROCESS_019","SOPC-INSTRUMENT_002"],"conclusiones":["GD05001, lámina 2: +3,800 m corresponde al techo de la caja de paso del expansor; +6,050 m al soporte SL401/402; +0,100 m al apoyo inferior. No equivalen a las alturas físicas de los expansores. Relación con cada envolvente del modelo pendiente de confirmar; se conservan los volúmenes provisionales."]}; JH_DimensionesDocumentadas - Dimensión X local del contorno CAD: 3.59094 m; Dimensión Y local del contorno CAD: 3.59 m
Caja fría del expansor norte · solo ámbito en planta; altura desconocida | Equipo pendiente de altura; plano fuente conservado | Plano del fabricante: implantación de equipos · referencia E7; Cimentaciones de equipos y pedestales del fabricante · revisión recibida 04/09/2026; Soportes de equipos SL1201 y SL401/402; Planta de estructuras metálicas; Plantas generales de instrumentación; Alumbrado de la caja fría | CB-EXP-N-PLAN | 4.00607 | 3.75823 | 0.1 | 286.2 | 286.3 | 25.0724 | 1.18472 | ["found_0904_f7e6bebab60859","found_0904_ab1632a7d9dd78","found_0904_e82a8a5ec7336e","found_0904_323dc0fbe26a0b","found_0904_3aab66a70a9bd0","found_0904_33c531229e93fa"] | references | Referencias documentales | no | survey_reference | Referencia documental · ámbar | [0.784314,0.584314,0.282353] | 1 | 0 | referencia | Interpretación visual del material documental; el acabado, tono y parámetros PBR no son una especificación contractual. | Apoyo relativo +0.100 m; cero absoluto provisional | {"name":"No especificado","source":"Sin especificación de material en la documentación revisada","status":"unknown"} | {"documented":[{"label":"Dimensión X local del contorno CAD","value":3.590056,"unit":"m","source":"EQ-IMPLANTACION-20260430 · contorno CAD · handles 91591,91592,91593,9159A","status":"derivado"},{"label":"Dimensión Y local del contorno CAD","value":3.3,"unit":"m","source":"EQ-IMPLANTACION-20260430 · contorno CAD · handles 91591,91592,91593,9159A","status":"derivado"},{"label":"Cota relativa de la superficie de apoyo","value":0.1,"unit":"m","source":"LHD2609-JG00100-20260904 · sección 4 / 4-4 / 4a-4a · 1FE9E, 1FF16, 1FF22","status":"documentado"}],"geometry":[{"label":"Extensión de la malla en X","value":4.006073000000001,"unit":"m","source":"Geometría releída del IFC; datum absoluto de proceso provisional","status":"derivado"},{"label":"Extensión de la malla en Y","value":3.758227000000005,"unit":"m","source":"Geometría releída del IFC; datum absoluto de proceso provisional","status":"derivado"},{"label":"Extensión de la malla en Z","value":0.09999999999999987,"unit":"m","source":"Geometría releída del IFC; datum absoluto de proceso provisional","status":"derivado"},{"label":"Cota inferior de visualización","value":286.20000000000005,"unit":"m","source":"Geometría releída del IFC; datum absoluto de proceso provisional","status":"derivado"},{"label":"Cota superior de visualización","value":286.3,"unit":"m","source":"Geometría releída del IFC; datum absoluto de proceso provisional","status":"derivado"}],"notes":["Las extensiones de la malla se miden en los ejes del proyecto tras el giro de implantación; no sustituyen las dimensiones locales del fabricante.","La envolvente, su volumen y los espesores de visualización no son volúmenes de material ni cantidades de compra, construcción o fabricación.","Las dimensiones documentadas distinguen cotas explícitas y medidas extraídas de contornos CAD; las dimensiones geométricas describen únicamente la malla publicada."]} | {"documentId":"EQ-IMPLANTACION-20260430","title":"Plano del fabricante: implantación de equipos · referencia E7","sheet":"Espacio modelo; referencia E7 en el nombre del archivo","date":"2026-04-30"} | {"Estado de la planta":"Derivado del CAD y del giro de implantación","Nivel relativo del apoyo (m)":0.1,"Estado del nivel relativo":"Documentado en el plano de cimentaciones","Cero absoluto de visualización (m)":286.1,"Estado del cero absoluto":"Provisional","Cota del apoyo de visualización (m)":286.20000000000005,"Desplazamiento aplicado a la malla (m)":0.10000000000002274,"Criterio":"Nivel de apoyo relativo documentado. Se adopta el cero de proceso a 286,10 m solo para visualización; la equivalencia absoluta no está confirmada. No se añade un espesor de montaje sin cota del fabricante."} | ["Marcador de 0,10 m de espesor: representa únicamente un ámbito en planta, no el cuerpo del equipo ni su altura física.","Cota de la plataforma elevada +0,100; losa exterior a 0,000. La relación XY de cada subcaja con la plataforma elevada debe verificarse en el modelo final.","Fondo ambiguo: sección 4-4 indica -1,000 pero cotas 1500 mm y sección 4a-4a indican -1,500.","El cero absoluto de la revisión no está definido; 286,10 m sigue siendo una hipótesis de coordinación.","Se alinea el punto inferior del conjunto del equipo, incluidos los pies ya representados, con la superficie de apoyo terminada; no se añade un espesor de calzos, placa o grout del fabricante no documentado.","GD05001, lámina 2: +3,800 m corresponde al techo de la caja de paso del expansor; +6,050 m al soporte SL401/402; +0,100 m al apoyo inferior. No equivalen a las alturas físicas de los expansores. Relación con cada envolvente del modelo pendiente de confirmar; se conservan los volúmenes provisionales.","DQ05000 H1 contiene cuatro alzados de alumbrado y LAMP1–15. El texto chino indica poste de 2,0 m y el inglés 2,5 m: discrepancia pendiente. Los alzados sin cotas no confirman la altura total del equipo ni los niveles de plataformas."] | {"boundingBoxM":{"min":[54.128395,45.830887,1.2],"max":[58.134468,49.589114,1.3]},"extentsM":[4.006073,3.758227,0.1],"meshSurfaceM2":25.072386,"meshVolumeM3":1.184719,"closedSolid":true,"basis":"Magnitudes de las mallas representadas, no cantidades certificadas de obra, compra o fabricación. Las partes pueden compartir superficies; no se suman como un despiece de materiales."} | {"material":false,"document":true,"quantities":true,"containerGuid":"17utmjd_LKsAVvPyuSUhFt","containerName":"Parcela industrial Jinhong"} | {"documentId":"LHD2609-JG00100-20260904","title":"Cimentaciones y pedestales de equipos · revisión recibida 04/09/2026","date":"2026-09-04","sheet":"4 / 4-4 / 4a-4a","sourceHandles":["1FE9E","1FF16","1FF22"]} | sourcePlanReference | unknown | {"valueM":null,"sourceSupported":false,"reason":"La altura propia de este módulo no figura en las fuentes revisadas. Los aproximadamente 30 m de la columna principal y las alturas de sus puntos de venteo no definen este módulo."} | {"id":"references","name":"Referencias documentales"} | {"profileId":"survey_reference","name":"Referencia documental · ámbar","materialName":"No especificado","physicalMaterialStatus":"unknown","physicalMaterialSource":"Sin especificación de material en la documentación revisada","appearanceStatus":"referencia","appearanceBasis":"Interpretación visual del material documental; el acabado, tono y parámetros PBR no son una especificación contractual.","note":"La apariencia gráfica no modifica ni confirma la especificación física del material."} | {"elementId":"CB-EXP-N-PLAN","ifcGuid":"1mMkw$v19ONubLDh62o1Rk","ifcClass":"IfcBuildingElementProxy","buildingId":"process_plant","buildingName":"Planta de proceso","sourceDocumentId":"EQ-IMPLANTACION-20260430","sourceRepresentationKind":"planReference"} | {"layerId":"references","layerName":"Referencias documentales","role":"Equipo pendiente de altura; plano fuente conservado","basis":"Clasificación por función del elemento; no modifica las especificaciones documentales."} | {"profileId":"survey_reference","name":"Referencia documental · ámbar","status":"referencia","basis":"Interpretación visual del material documental; el acabado, tono y parámetros PBR no son una especificación contractual.","physicalMaterialUnchanged":true} | 4 | Únicamente se identifica un ámbito en planta; altura física del equipo sin confirmar. | Nivel de apoyo relativo documentado. Se adopta el cero de proceso a 286,10 m solo para visualización; la equivalencia absoluta no está confirmada. No se añade un espesor de montaje sin cota del fabricante. | Plano del fabricante: implantación de equipos · referencia E7 · 2026-04-30 · Espacio modelo; referencia E7 en el nombre del archivo | 91591,91592,91593,9159A | Contorno del equipo representado con línea de doble trazo y punto dentro del bloque CAD activo del fabricante. El contorno grueso exterior corresponde a la cimentación y no se adopta como envolvente del equipo. | 27 × 57 m; dimensiones acotadas en el plano general. | El punto de referencia del fabricante coincide con la esquina suroeste de la zona de equipos. Giro local de −7,82824° para la implantación en coordenadas UTM. | Coordenadas locales del proyecto en metros. Añadir (729400, 4301550, 285) para recuperar las coordenadas UTM y las cotas del plano. | Sólido IFC4 mediante malla triangular cerrada | Los equipos se representan mediante envolventes. Los espesores y alturas supuestos y el volumen de las envolventes no representan cantidades de materiales, compras, construcción o fabricación. | provisional | 0.1 | Pendiente de plano del fabricante | Geometría de coordinación basada en planos recibidos; no sustituye el modelo de fabricación ni una medición certificada. Datum absoluto de proceso provisional. | Sin especificación de material en la documentación revisada | Equipos; Zona de separación de aire; BIM · Referencias documentales | JH_RevisionDocumental20260909 - Criterio: Documentación complementaria recibida el 09/09/2026. Tuberías: paquete actualizado el 07/08; fechas y revisiones por plano. La recepción no cambia la fecha de diseño. Se mantienen cargas del 25/08 y cimentaciones recibidas el 04/09 frente a las versiones anteriores incluidas.; Documentos: SOPC-PROCESS_020 | SOPC-PROCESS_019 | SOPC-INSTRUMENT_002; Conclusiones: GD05001, lámina 2: +3,800 m corresponde al techo de la caja de paso del expansor; +6,050 m al soporte SL401/402; +0,100 m al apoyo inferior. No equivalen a las alturas físicas de los expansores. Relación con cada envolvente del modelo pendiente de confirmar; se conservan los volúmenes provisionales.; GeometriaModificada: no; JH_InformacionBIM - supplementaryDrawingReview: {"fecha":"2026-09-09","estado":"Revisión documental; geometría conservada","criterio":"Documentación complementaria recibida el 09/09/2026. Tuberías: paquete actualizado el 07/08; fechas y revisiones por plano. La recepción no cambia la fecha de diseño. Se mantienen cargas del 25/08 y cimentaciones recibidas el 04/09 frente a las versiones anteriores incluidas.","documentos":["SOPC-PROCESS_020","SOPC-PROCESS_019","SOPC-INSTRUMENT_002","SOPC-ELECTRICAL_003"],"conclusiones":["GD05001, lámina 2: +3,800 m corresponde al techo de la caja de paso del expansor; +6,050 m al soporte SL401/402; +0,100 m al apoyo inferior. No equivalen a las alturas físicas de los expansores. Relación con cada envolvente del modelo pendiente de confirmar; se conservan los volúmenes provisionales.","DQ05000 H1 contiene cuatro alzados de alumbrado y LAMP1–15. El texto chino indica poste de 2,0 m y el inglés 2,5 m: discrepancia pendiente. Los alzados sin cotas no confirman la altura total del equipo ni los niveles de plataformas."]}; JH_Trazabilidad - Bloque CAD: 14257432; Identificador CAD de la inserción (handle): 9122B; Identificador CAD del rótulo (handle): 9159D; Origen de la altura: No se ha localizado una altura acotada del equipo.; Alcance de la geometría: Marcador del ámbito en planta; Dimensión X local del contorno (m): 3.59006; Dimensión Y local del contorno (m): 3.3; Capa: Equipos pendientes de altura; Revisión documental complementaria: {"fecha":"2026-09-09","estado":"Revisión documental; geometría conservada","criterio":"Documentación complementaria recibida el 09/09/2026. Tuberías: paquete actualizado el 07/08; fechas y revisiones por plano. La recepción no cambia la fecha de diseño. Se mantienen cargas del 25/08 y cimentaciones recibidas el 04/09 frente a las versiones anteriores incluidas.","documentos":["SOPC-PROCESS_020","SOPC-PROCESS_019","SOPC-INSTRUMENT_002"],"conclusiones":["GD05001, lámina 2: +3,800 m corresponde al techo de la caja de paso del expansor; +6,050 m al soporte SL401/402; +0,100 m al apoyo inferior. No equivalen a las alturas físicas de los expansores. Relación con cada envolvente del modelo pendiente de confirmar; se conservan los volúmenes provisionales."]}; JH_DimensionesDocumentadas - Dimensión X local del contorno CAD: 3.59006 m; Dimensión Y local del contorno CAD: 3.3 m
Caja fría del expansor oeste · solo ámbito en planta; altura desconocida | Equipo pendiente de altura; plano fuente conservado | Plano del fabricante: implantación de equipos · referencia E7; Cimentaciones de equipos y pedestales del fabricante · revisión recibida 04/09/2026; Soportes de equipos SL1201 y SL401/402; Planta de estructuras metálicas; Plantas generales de instrumentación; Alumbrado de la caja fría | CB-EXP-W-PLAN | 3.75822 | 4.00602 | 0.1 | 286.2 | 286.3 | 25.072 | 1.1847 | ["found_0904_f7e6bebab60859","found_0904_ab1632a7d9dd78","found_0904_e82a8a5ec7336e","found_0904_323dc0fbe26a0b","found_0904_3aab66a70a9bd0","found_0904_33c531229e93fa"] | references | Referencias documentales | no | survey_reference | Referencia documental · ámbar | [0.784314,0.584314,0.282353] | 1 | 0 | referencia | Interpretación visual del material documental; el acabado, tono y parámetros PBR no son una especificación contractual. | Apoyo relativo +0.100 m; cero absoluto provisional | {"name":"No especificado","source":"Sin especificación de material en la documentación revisada","status":"unknown"} | {"documented":[{"label":"Dimensión X local del contorno CAD","value":3.3000000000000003,"unit":"m","source":"EQ-IMPLANTACION-20260430 · contorno CAD · handles 91590,91598,91599,91453","status":"derivado"},{"label":"Dimensión Y local del contorno CAD","value":3.59,"unit":"m","source":"EQ-IMPLANTACION-20260430 · contorno CAD · handles 91590,91598,91599,91453","status":"derivado"},{"label":"Cota relativa de la superficie de apoyo","value":0.1,"unit":"m","source":"LHD2609-JG00100-20260904 · sección 4 / 4-4 / 4a-4a · 1FE9E, 1FF16, 1FF22","status":"documentado"}],"geometry":[{"label":"Extensión de la malla en X","value":3.758218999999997,"unit":"m","source":"Geometría releída del IFC; datum absoluto de proceso provisional","status":"derivado"},{"label":"Extensión de la malla en Y","value":4.006017,"unit":"m","source":"Geometría releída del IFC; datum absoluto de proceso provisional","status":"derivado"},{"label":"Extensión de la malla en Z","value":0.09999999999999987,"unit":"m","source":"Geometría releída del IFC; datum absoluto de proceso provisional","status":"derivado"},{"label":"Cota inferior de visualización","value":286.20000000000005,"unit":"m","source":"Geometría releída del IFC; datum absoluto de proceso provisional","status":"derivado"},{"label":"Cota superior de visualización","value":286.3,"unit":"m","source":"Geometría releída del IFC; datum absoluto de proceso provisional","status":"derivado"}],"notes":["Las extensiones de la malla se miden en los ejes del proyecto tras el giro de implantación; no sustituyen las dimensiones locales del fabricante.","La envolvente, su volumen y los espesores de visualización no son volúmenes de material ni cantidades de compra, construcción o fabricación.","Las dimensiones documentadas distinguen cotas explícitas y medidas extraídas de contornos CAD; las dimensiones geométricas describen únicamente la malla publicada."]} | {"documentId":"EQ-IMPLANTACION-20260430","title":"Plano del fabricante: implantación de equipos · referencia E7","sheet":"Espacio modelo; referencia E7 en el nombre del archivo","date":"2026-04-30"} | {"Estado de la planta":"Derivado del CAD y del giro de implantación","Nivel relativo del apoyo (m)":0.1,"Estado del nivel relativo":"Documentado en el plano de cimentaciones","Cero absoluto de visualización (m)":286.1,"Estado del cero absoluto":"Provisional","Cota del apoyo de visualización (m)":286.20000000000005,"Desplazamiento aplicado a la malla (m)":0.10000000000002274,"Criterio":"Nivel de apoyo relativo documentado. Se adopta el cero de proceso a 286,10 m solo para visualización; la equivalencia absoluta no está confirmada. No se añade un espesor de montaje sin cota del fabricante."} | ["Marcador de 0,10 m de espesor: representa únicamente un ámbito en planta, no el cuerpo del equipo ni su altura física.","Cota de la plataforma elevada +0,100; losa exterior a 0,000. La relación XY de cada subcaja con la plataforma elevada debe verificarse en el modelo final.","Fondo ambiguo: sección 4-4 indica -1,000 pero cotas 1500 mm y sección 4a-4a indican -1,500.","El cero absoluto de la revisión no está definido; 286,10 m sigue siendo una hipótesis de coordinación.","Se alinea el punto inferior del conjunto del equipo, incluidos los pies ya representados, con la superficie de apoyo terminada; no se añade un espesor de calzos, placa o grout del fabricante no documentado.","GD05001, lámina 2: +3,800 m corresponde al techo de la caja de paso del expansor; +6,050 m al soporte SL401/402; +0,100 m al apoyo inferior. No equivalen a las alturas físicas de los expansores. Relación con cada envolvente del modelo pendiente de confirmar; se conservan los volúmenes provisionales.","DQ05000 H1 contiene cuatro alzados de alumbrado y LAMP1–15. El texto chino indica poste de 2,0 m y el inglés 2,5 m: discrepancia pendiente. Los alzados sin cotas no confirman la altura total del equipo ni los niveles de plataformas."] | {"boundingBoxM":{"min":[50.369247,42.763451,1.2],"max":[54.127466,46.769468,1.3]},"extentsM":[3.758219,4.006017,0.1],"meshSurfaceM2":25.072001,"meshVolumeM3":1.1847,"closedSolid":true,"basis":"Magnitudes de las mallas representadas, no cantidades certificadas de obra, compra o fabricación. Las partes pueden compartir superficies; no se suman como un despiece de materiales."} | {"material":false,"document":true,"quantities":true,"containerGuid":"17utmjd_LKsAVvPyuSUhFt","containerName":"Parcela industrial Jinhong"} | {"documentId":"LHD2609-JG00100-20260904","title":"Cimentaciones y pedestales de equipos · revisión recibida 04/09/2026","date":"2026-09-04","sheet":"4 / 4-4 / 4a-4a","sourceHandles":["1FE9E","1FF16","1FF22"]} | sourcePlanReference | unknown | {"valueM":null,"sourceSupported":false,"reason":"La altura propia de este módulo no figura en las fuentes revisadas. Los aproximadamente 30 m de la columna principal y las alturas de sus puntos de venteo no definen este módulo."} | {"id":"references","name":"Referencias documentales"} | {"profileId":"survey_reference","name":"Referencia documental · ámbar","materialName":"No especificado","physicalMaterialStatus":"unknown","physicalMaterialSource":"Sin especificación de material en la documentación revisada","appearanceStatus":"referencia","appearanceBasis":"Interpretación visual del material documental; el acabado, tono y parámetros PBR no son una especificación contractual.","note":"La apariencia gráfica no modifica ni confirma la especificación física del material."} | {"elementId":"CB-EXP-W-PLAN","ifcGuid":"00wEdKRtzUVQDHurWH5Zbb","ifcClass":"IfcBuildingElementProxy","buildingId":"process_plant","buildingName":"Planta de proceso","sourceDocumentId":"EQ-IMPLANTACION-20260430","sourceRepresentationKind":"planReference"} | {"layerId":"references","layerName":"Referencias documentales","role":"Equipo pendiente de altura; plano fuente conservado","basis":"Clasificación por función del elemento; no modifica las especificaciones documentales."} | {"profileId":"survey_reference","name":"Referencia documental · ámbar","status":"referencia","basis":"Interpretación visual del material documental; el acabado, tono y parámetros PBR no son una especificación contractual.","physicalMaterialUnchanged":true} | 4 | Únicamente se identifica un ámbito en planta; altura física del equipo sin confirmar. | Nivel de apoyo relativo documentado. Se adopta el cero de proceso a 286,10 m solo para visualización; la equivalencia absoluta no está confirmada. No se añade un espesor de montaje sin cota del fabricante. | Plano del fabricante: implantación de equipos · referencia E7 · 2026-04-30 · Espacio modelo; referencia E7 en el nombre del archivo | 91590,91598,91599,91453 | Contorno del equipo representado con línea de doble trazo y punto dentro del bloque CAD activo del fabricante. El contorno grueso exterior corresponde a la cimentación y no se adopta como envolvente del equipo. | 27 × 57 m; dimensiones acotadas en el plano general. | El punto de referencia del fabricante coincide con la esquina suroeste de la zona de equipos. Giro local de −7,82824° para la implantación en coordenadas UTM. | Coordenadas locales del proyecto en metros. Añadir (729400, 4301550, 285) para recuperar las coordenadas UTM y las cotas del plano. | Sólido IFC4 mediante malla triangular cerrada | Los equipos se representan mediante envolventes. Los espesores y alturas supuestos y el volumen de las envolventes no representan cantidades de materiales, compras, construcción o fabricación. | provisional | 0.1 | Pendiente de plano del fabricante | Geometría de coordinación basada en planos recibidos; no sustituye el modelo de fabricación ni una medición certificada. Datum absoluto de proceso provisional. | Sin especificación de material en la documentación revisada | Equipos; Zona de separación de aire; BIM · Referencias documentales | JH_RevisionDocumental20260909 - Criterio: Documentación complementaria recibida el 09/09/2026. Tuberías: paquete actualizado el 07/08; fechas y revisiones por plano. La recepción no cambia la fecha de diseño. Se mantienen cargas del 25/08 y cimentaciones recibidas el 04/09 frente a las versiones anteriores incluidas.; Documentos: SOPC-PROCESS_020 | SOPC-PROCESS_019 | SOPC-INSTRUMENT_002; Conclusiones: GD05001, lámina 2: +3,800 m corresponde al techo de la caja de paso del expansor; +6,050 m al soporte SL401/402; +0,100 m al apoyo inferior. No equivalen a las alturas físicas de los expansores. Relación con cada envolvente del modelo pendiente de confirmar; se conservan los volúmenes provisionales.; GeometriaModificada: no; JH_InformacionBIM - supplementaryDrawingReview: {"fecha":"2026-09-09","estado":"Revisión documental; geometría conservada","criterio":"Documentación complementaria recibida el 09/09/2026. Tuberías: paquete actualizado el 07/08; fechas y revisiones por plano. La recepción no cambia la fecha de diseño. Se mantienen cargas del 25/08 y cimentaciones recibidas el 04/09 frente a las versiones anteriores incluidas.","documentos":["SOPC-PROCESS_020","SOPC-PROCESS_019","SOPC-INSTRUMENT_002","SOPC-ELECTRICAL_003"],"conclusiones":["GD05001, lámina 2: +3,800 m corresponde al techo de la caja de paso del expansor; +6,050 m al soporte SL401/402; +0,100 m al apoyo inferior. No equivalen a las alturas físicas de los expansores. Relación con cada envolvente del modelo pendiente de confirmar; se conservan los volúmenes provisionales.","DQ05000 H1 contiene cuatro alzados de alumbrado y LAMP1–15. El texto chino indica poste de 2,0 m y el inglés 2,5 m: discrepancia pendiente. Los alzados sin cotas no confirman la altura total del equipo ni los niveles de plataformas."]}; JH_Trazabilidad - Bloque CAD: 14257432; Identificador CAD de la inserción (handle): 9122B; Identificador CAD del rótulo (handle): 9159E; Origen de la altura: No se ha localizado una altura acotada del equipo.; Alcance de la geometría: Marcador del ámbito en planta; Dimensión X local del contorno (m): 3.3; Dimensión Y local del contorno (m): 3.59; Capa: Equipos pendientes de altura; Revisión documental complementaria: {"fecha":"2026-09-09","estado":"Revisión documental; geometría conservada","criterio":"Documentación complementaria recibida el 09/09/2026. Tuberías: paquete actualizado el 07/08; fechas y revisiones por plano. La recepción no cambia la fecha de diseño. Se mantienen cargas del 25/08 y cimentaciones recibidas el 04/09 frente a las versiones anteriores incluidas.","documentos":["SOPC-PROCESS_020","SOPC-PROCESS_019","SOPC-INSTRUMENT_002"],"conclusiones":["GD05001, lámina 2: +3,800 m corresponde al techo de la caja de paso del expansor; +6,050 m al soporte SL401/402; +0,100 m al apoyo inferior. No equivalen a las alturas físicas de los expansores. Relación con cada envolvente del modelo pendiente de confirmar; se conservan los volúmenes provisionales."]}; JH_DimensionesDocumentadas - Dimensión X local del contorno CAD: 3.3 m; Dimensión Y local del contorno CAD: 3.59 m
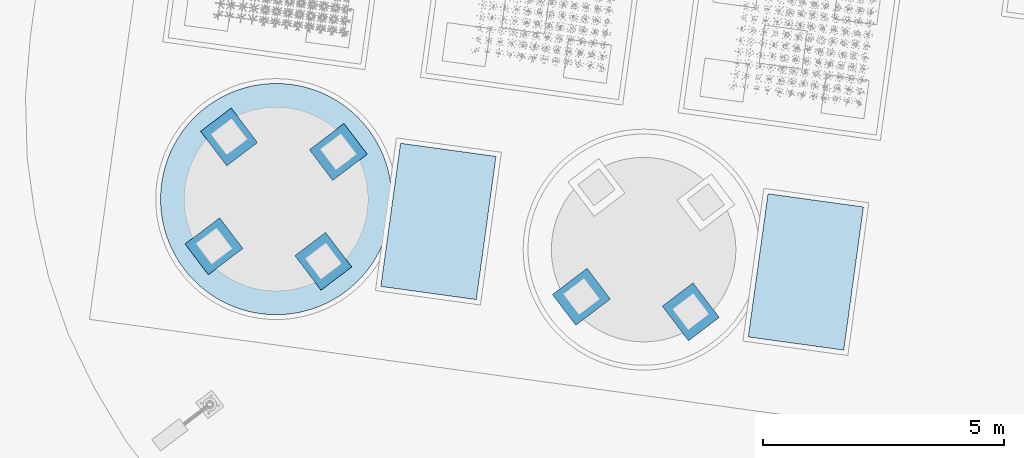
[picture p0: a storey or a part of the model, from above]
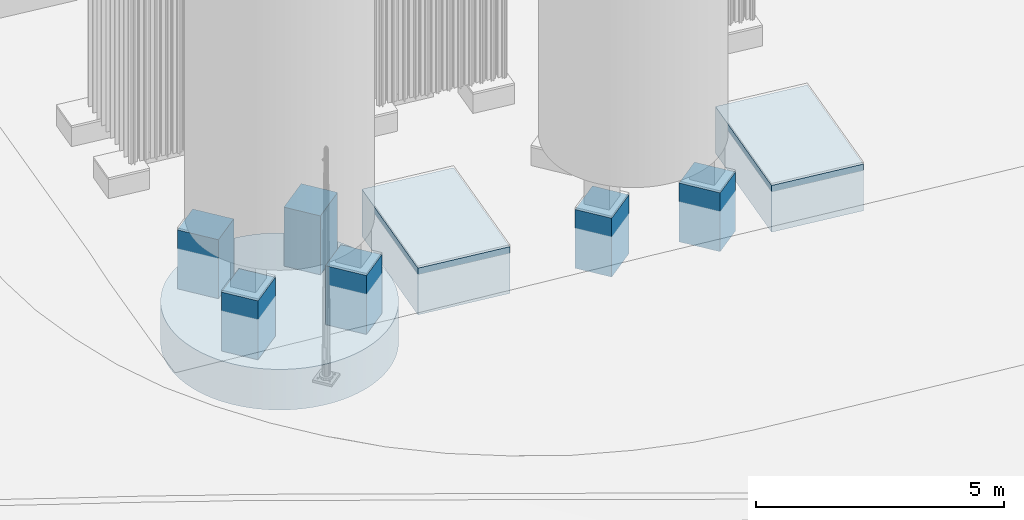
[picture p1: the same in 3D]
Properties of the parts of a building model (IFC4), part 55 of 134

# IfcBuildingElementProxy: Marcador de equipo en planta (6)
Name | Description = Funcion = category = Categoria | Document | Reference = Identificador del objeto = Identificador | Extensión de la malla en X (m) = ExtensionX (m) | Extensión de la malla en Y (m) = ExtensionY (m) | Extensión de la malla en Z (m) = ExtensionZ (m) | Cota inferior de visualización (m) | Cota superior de visualización (m) | SuperficieDeLaMalla (m2) | VolumenGeometrico (m3) | ElementosDeCimentacion = foundationIds | IdentificadorCapa = layerId | NombreCapa = Capa BIM | VisibilidadInicial | Perfil | Acabado = Acabado de visualización | ColorRGB | Rugosidad | Metallicidad | Estado = Estado del acabado | Referencia | level | material | dimensions | JH_InformacionBIM, source = DocumentoFuente | positioning = PosicionYEstado | issues = IncidenciasPendientes | geometryMetrics | ifcAssociations | installationSource = Fuente del nivel de apoyo | representationKind | JH_InformacionBIM, heightStatus | heightReference | visualLayer | materialAppearance | visualizationIdentity | classification | appearance | Referencia en el plano del fabricante | Grado de definición | Hipótesis de modelado = Estado de la cota de instalación | Documento de origen | Identificadores CAD del contorno (handles) | Origen de las dimensiones | Dimensiones de la plataforma de equipos (m) | Implantación de la plataforma de equipos | Convención de coordenadas | Representación geométrica IFC | Aplicabilidad a mediciones | Estado de la información | Nivel relativo de apoyo documentado (m) = Cota relativa de la superficie de apoyo (m) | Estado de altura | UsoDeLasMagnitudes | JH_EvidenciaDeMaterial, source | Group
Adsorbedor MS1202 · volumen de referencia H 7,30 m | Volumen de referencia de altura; no geometría de fabricación | Plano del fabricante: cargas de equipos; Plano del fabricante: implantación de equipos · referencia E7; Cimentaciones de equipos y pedestales del fabricante · revisión recibida 04/09/2026 | PPU-A-PLAN | 3.6311 | 3.6304 | 7.3 | 286.2 | 293.5 | 103.942 | 75.5176 | ["found_0904_c3bd5e0d38836a","found_0904_a16d8875227a01","found_0904_bc40ce234e571f"] | equipment | Equipos | yes | equipment_light_gray | Equipo · gris claro provisional | [0.88,0.89,0.88] | 0.45 | 0.28 | provisional | Referencia visual de fotografías públicas de Jinhong Gas / fabricante. Apariencia provisional para coordinación; fotografías oficiales pueden orientar el color, pero no acreditan el material, el acabado ni el equipo concreto. | Apoyo relativo +0.100 m; cero absoluto provisional | {"name":"No especificado","source":"Los contornos revisados no especifican el material del equipo.","status":"unknown"} | {"documented":[{"label":"Diámetro exterior ajustado al contorno CAD","value":3.630197,"unit":"m","source":"EQ-IMPLANTACION-20260430 · polilínea 9C278","status":"derivado"},{"label":"Error radial máximo del ajuste","value":0.001262,"unit":"m","source":"EQ-IMPLANTACION-20260430 · polilínea 9C278","status":"derivado"},{"label":"Número de huellas de apoyo","value":4,"unit":"ud","source":"EQ-IMPLANTACION-20260430 · 9C279,9C27A,9C27B,9C27C","status":"derivado"},{"label":"Cota relativa de la superficie de apoyo","value":0.1,"unit":"m","source":"LHD2609-JG00100-20260904 · sección 3 / 3-3 · 28D00, 28D41","status":"documentado"}],"geometry":[{"label":"Extensión de la malla en X","value":3.631097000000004,"unit":"m","source":"Geometría releída del IFC; datum absoluto de proceso provisional","status":"derivado"},{"label":"Extensión de la malla en Y","value":3.6304000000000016,"unit":"m","source":"Geometría releída del IFC; datum absoluto de proceso provisional","status":"derivado"},{"label":"Extensión de la malla en Z","value":7.3,"unit":"m","source":"Geometría releída del IFC; datum absoluto de proceso provisional","status":"derivado"},{"label":"Cota inferior de visualización","value":286.2,"unit":"m","source":"Geometría releída del IFC; datum absoluto de proceso provisional","status":"derivado"},{"label":"Cota superior de visualización","value":293.5,"unit":"m","source":"Geometría releída del IFC; datum absoluto de proceso provisional","status":"derivado"}],"notes":["Geometría exterior de referencia; los volúmenes no representan cantidades de material, compra o fabricación."],"reference":[{"label":"Altura de referencia","value":7.3,"unit":"m","source":"SRC-MEETING-20260720-162843","status":"provisional"}]} | {"documentId":"EQ-IMPLANTACION-20260430","title":"Plano del fabricante: implantación de equipos · referencia E7","sheet":"Espacio modelo; referencia E7 en el nombre del archivo","date":"2026-04-30"} | {"Estado de la planta":"Derivado del CAD y del giro de implantación","Nivel relativo del apoyo (m)":0.1,"Estado del nivel relativo":"Documentado en el plano de cimentaciones","Cero absoluto de visualización (m)":286.1,"Estado del cero absoluto":"Provisional","Cota del apoyo de visualización (m)":286.20000000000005,"Desplazamiento aplicado a la malla (m)":0.10000000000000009,"Criterio":"Se conserva exactamente la base y posición XY publicadas; solo se sustituye la altura gráfica por una referencia atribuida. No se alteran las cimentaciones."} | ["Altura verbal de 7,30 m citada en la reunión del 20/07/2026 a las 16:28:43, aplicada provisionalmente a los dos adsorbedores. No es una cota confirmada de fabricante ni define la longitud de virola.","Envolvente de referencia obtenida al prolongar únicamente el contorno exterior del cuerpo CAD; las cuatro huellas de patas permanecen en el plano fuente. No se representan patas altas ni fondos curvos inventados.","Este volumen es conmutable por capa y no se utiliza como medición, gálibo certificado, capacidad ni definición de fabricación.","Cara superior de grout HA-35 de 50 mm a +0,100; hormigón a +0,050.","El cero absoluto de la revisión no está definido; 286,10 m sigue siendo una hipótesis de coordinación.","Se alinea el punto inferior del conjunto del equipo, incluidos los pies ya representados, con la superficie de apoyo terminada; no se añade un espesor de calzos, placa o grout del fabricante no documentado."] | {"boundingBoxM":{"min":[48.777674,54.788236,1.2],"max":[52.408771,58.418636,8.5]},"extentsM":[3.631097,3.6304,7.3],"meshSurfaceM2":103.941961,"meshVolumeM3":75.517617,"closedSolid":true,"basis":"Geometría de coordinación. Los volúmenes de referencia y subcomponentes no son cantidades de material ni componentes de fabricación certificados."} |  | {"documentId":"LHD2609-JG00100-20260904","title":"Cimentaciones y pedestales de equipos · revisión recibida 04/09/2026","date":"2026-09-04","sheet":"3 / 3-3","sourceHandles":["28D00","28D41"]} | referenceVolume | provisional | {"valueM":7.3,"status":"provisional","sourceRef":"SRC-MEETING-20260720-162843","baseModelZM":1.2,"baseAbsoluteVisualizationM":286.2,"fromFinishedFoundationSupport":true,"scope":"whole-equipment-envelope","sourceNote":"Altura verbal de 7,30 m citada en la reunión del 20/07/2026 a las 16:28:43, aplicada provisionalmente a los dos adsorbedores. No es una cota confirmada de fabricante ni define la longitud de virola.","sourcePlanObjectId":"SOURCE-PLAN-PPU-A-PLAN","sourcePlanGuid":"3AP7q$u_jKiAGEQ2N$61Za"} | {"id":"equipment","name":"Equipos"} | {"profileId":"equipment_light_gray","name":"Equipo · gris claro provisional","materialName":"No especificado","physicalMaterialStatus":"unknown","physicalMaterialSource":"Los contornos revisados no especifican el material del equipo.","appearanceStatus":"provisional","appearanceBasis":"Referencia visual de fotografías públicas de Jinhong Gas / fabricante. Apariencia provisional para coordinación; fotografías oficiales pueden orientar el color, pero no acreditan el material, el acabado ni el equipo concreto.","note":"La apariencia gráfica no modifica ni confirma la especificación física del material."} | {"elementId":"PPU-A-PLAN","ifcGuid":"2O$9mJixLME8AOrxnEUH3D","ifcClass":"IfcBuildingElementProxy","buildingId":"process_plant","buildingName":"Planta de proceso","sourceDocumentId":"EQ-IMPLANTACION-20260430","sourceRepresentationKind":"planReference"} | {"layerId":"equipment","layerName":"Equipos","role":"Volumen de referencia de altura; no geometría de fabricación","basis":"Clasificación por función del elemento; no modifica las especificaciones documentales."} | {"profileId":"equipment_light_gray","name":"Equipo · gris claro provisional","status":"provisional","basis":"Referencia visual de fotografías públicas de Jinhong Gas / fabricante. Apariencia provisional para coordinación; fotografías oficiales pueden orientar el color, pero no acreditan el material, el acabado ni el equipo concreto.","physicalMaterialUnchanged":true} |  | Altura verbal de 7,30 m citada en la reunión del 20/07/2026 a las 16:28:43, aplicada provisionalmente a los dos adsorbedores. No es una cota confirmada de fabricante ni define la longitud de virola. Envolvente de referencia obtenida al prolongar únicamente el contorno exterior del cuerpo CAD; las cuatro huellas de patas permanecen en el plano fuente. No se representan patas altas ni fondos curvos inventados. |  | Plano del fabricante: implantación de equipos · referencia E7 | 9C278, 9C279, 9C27A, 9C27B, 9C27C |  |  |  | Metros en la plataforma local del fabricante; transformación de implantación aplicada durante la integración. |  | Referencia gráfica conmutable; no apta para medición, fabricación ni verificación certificada de interferencias. | Altura de referencia provisional | 0.1 | provisional | Geometría de coordinación. Los volúmenes de referencia y subcomponentes no son cantidades de material ni componentes de fabricación certificados. | Los contornos revisados no especifican el material del equipo. | Equipos; Zona de separación de aire; BIM · Equipos | JH_InformacionBIM - detailGeometry: {"source":{"documentId":"EQ-IMPLANTACION-20260430","title":"Plano del fabricante: implantación de equipos · referencia E7","sheet":"Espacio modelo; referencia E7 en el nombre del archivo","date":"2026-04-30"},"cadSource":"equipment_layout.dxf","conversion":"ODA","sourceInsertHandle":"8DD29","limitations":["La altura física del adsorbedor no está documentada; se conserva una referencia en planta de 0,10 m de espesor visual.","Se conserva cada vértice del contorno exterior CAD y las cuatro huellas de apoyo. El corte gráfico de la boquilla se cierra con una cuerda únicamente para cerrar la malla.","La circunferencia de ejes de 3,906 m corresponde a anclajes y no al diámetro exterior; queda excluida de la geometría de carcasa.","Las cotas verticales y la geometría de patas y boquillas requieren un alzado del fabricante."],"planMarkerThicknessM":0.1,"closureGapM":0.456618,"method":"Vertical extension of an existing closed source-plan component; identical XY and base Z.","sourceObjectId":"PPU-A-PLAN","sourceObjectGuid":"2O$9mJixLME8AOrxnEUH3D","sourceRefs":["SRC-V4-PUBLISHED-MODEL","SRC-EQUIPMENT-RECHECK","SRC-MEETING-20260720-162843"],"sourceVertexIndices":[0,1,2,3,4,5,6,7,8,9,10,11,12,13,14,15,16,17,18,19,20,21,22,23,24,25,26,27,28,29,30,31,32,33,34,35,36,37,38,39,40,41,42,43,44,45,46,47,48,49,50,51,52,53,54,55,56,57,58,59,60,61,62,63,64,65,66,67,68,69,70,71,72,73,74,75,76,77,78,79,80,81,82,83,84,85,86,87,88,89,90,91,92,93,94,95,96,97,98,99,100,101,102,103,104,105,106,107,108,109,110,111,112,113,114,115,116,117,118,119,120,121,122,123,124,125,126,127,128,129,130,131,132,133,134,135,136,137,138,139,140,141,142,143,144,145,146,147,148,149,150,151,152,153,154,155,156,157,158,159,160,161,162,163,164,165,166,167,168,169,170,171,172,173,174,175,176,177,178,179,180,181,182,183,184,185,186,187,188,189,190,191,192,193,194,195,196,197,198,199,200,201,202,203,204,205,206,207,208,209,210,211,212,213,214,215,216,217,218,219,220,221,222,223,224,225,226,227,228,229,230,231,232,233,234,235,236,237,238,239,240,241,242,243,244,245,246,247,248,249,250,251,252,253,254,255,256,257,258,259,260,261,262,263,264,265,266,267,268,269,270,271,272,273,274,275,276,277,278,279,280,281,282,283,284,285,286,287,288,289,290,291,292,293,294,295,296,297,298,299,300,301,302,303,304,305,306,307,308,309,310,311,312,313,314,315,316,317,318,319,320,321,322,323,324,325,326,327,328,329,330,331,332,333,334,335,336,337,338,339,340,341,342,343,344,345,346,347,348,349,350,351,352,353,354,355,356,357,358,359,360,361,362,363,364,365,366,367,368,369,370,371,372,373,374,375,376,377,378,379,380,381,382,383,384,385,386,387,388,389,390,391,392,393,394,395,396,397,398,399,400,401,402,403,404,405,406,407,408,409,410,411,412,413,414,415,416,417,418,419,420,421,422,423,424,425,426,427,428,429,430,431,432,433,434,435,436,437,438,439,440,441,442,443,444,445,446,447,448,449,450,451,452,453,454,455,456,457,458,459,460,461,462,463,464,465],"sourcePartCount":5,"heightReferenceM":7.3,"heightStatus":"provisional","planReferenceObjectId":"SOURCE-PLAN-PPU-A-PLAN","unconfirmedDimensions":["Actual equipment height and construction geometry remain unconfirmed."],"sourceGeometryClassification":"conceptual_envelope","partsAreBOM":false}; heightKind: oralReferenceEnvelope; physicalHeightConfirmed: no; quantityEligible: no; visualizationGeometryStatus: Volumen ilustrativo provisional; no sustituye cotas verificadas del fabricante.; JH_Trazabilidad - Altura de referencia (m): 7.3; Referencia de plano conservada: SOURCE-PLAN-PPU-A-PLAN; JH_DimensionesDocumentadas - Diámetro exterior ajustado al contorno CAD: 3.6302 m; Error radial máximo del ajuste: 0.001262 m; Número de huellas de apoyo: 4; JH_DetalleGeometrico - source: {"documentId":"EQ-IMPLANTACION-20260430","title":"Plano del fabricante: implantación de equipos · referencia E7","sheet":"Espacio modelo; referencia E7 en el nombre del archivo","date":"2026-04-30"}; cadSource: equipment_layout.dxf; conversion: ODA; sourceInsertHandle: 8DD29; limitations: ["La altura física del adsorbedor no está documentada; se conserva una referencia en planta de 0,10 m de espesor visual.","Se conserva cada vértice del contorno exterior CAD y las cuatro huellas de apoyo. El corte gráfico de la boquilla se cierra con una cuerda únicamente para cerrar la malla.","La circunferencia de ejes de 3,906 m corresponde a anclajes y no al diámetro exterior; queda excluida de la geometría de carcasa.","Las cotas verticales y la geometría de patas y boquillas requieren un alzado del fabricante."]; planMarkerThicknessM: 0.1; closureGapM: 0.456618; method: Vertical extension of an existing closed source-plan component; identical XY and base Z.; sourceObjectId: PPU-A-PLAN; sourceRefs: ["SRC-V4-PUBLISHED-MODEL","SRC-EQUIPMENT-RECHECK","SRC-MEETING-20260720-162843"]; sourceVertexIndices: [0,1,2,3,4,5,6,7,8,9,10,11,12,13,14,15,16,17,18,19,20,21,22,23,24,25,26,27,28,29,30,31,32,33,34,35,36,37,38,39,40,41,42,43,44,45,46,47,48,49,50,51,52,53,54,55,56,57,58,59,60,61,62,63,64,65,66,67,68,69,70,71,72,73,74,75,76,77,78,79,80,81,82,83,84,85,86,87,88,89,90,91,92,93,94,95,96,97,98,99,100,101,102,103,104,105,106,107,108,109,110,111,112,113,114,115,116,117,118,119,120,121,122,123,124,125,126,127,128,129,130,131,132,133,134,135,136,137,138,139,140,141,142,143,144,145,146,147,148,149,150,151,152,153,154,155,156,157,158,159,160,161,162,163,164,165,166,167,168,169,170,171,172,173,174,175,176,177,178,179,180,181,182,183,184,185,186,187,188,189,190,191,192,193,194,195,196,197,198,199,200,201,202,203,204,205,206,207,208,209,210,211,212,213,214,215,216,217,218,219,220,221,222,223,224,225,226,227,228,229,230,231,232,233,234,235,236,237,238,239,240,241,242,243,244,245,246,247,248,249,250,251,252,253,254,255,256,257,258,259,260,261,262,263,264,265,266,267,268,269,270,271,272,273,274,275,276,277,278,279,280,281,282,283,284,285,286,287,288,289,290,291,292,293,294,295,296,297,298,299,300,301,302,303,304,305,306,307,308,309,310,311,312,313,314,315,316,317,318,319,320,321,322,323,324,325,326,327,328,329,330,331,332,333,334,335,336,337,338,339,340,341,342,343,344,345,346,347,348,349,350,351,352,353,354,355,356,357,358,359,360,361,362,363,364,365,366,367,368,369,370,371,372,373,374,375,376,377,378,379,380,381,382,383,384,385,386,387,388,389,390,391,392,393,394,395,396,397,398,399,400,401,402,403,404,405,406,407,408,409,410,411,412,413,414,415,416,417,418,419,420,421,422,423,424,425,426,427,428,429,430,431,432,433,434,435,436,437,438,439,440,441,442,443,444,445,446,447,448,449,450,451,452,453,454,455,456,457,458,459,460,461,462,463,464,465]; sourcePartCount: 5; heightReferenceM: 7.3; heightStatus: provisional; planReferenceObjectId: SOURCE-PLAN-PPU-A-PLAN; unconfirmedDimensions: ["Actual equipment height and construction geometry remain unconfirmed."]; sourceGeometryClassification: conceptual_envelope; partsAreBOM: no
Adsorbedor MS1201 · volumen de referencia H 7,30 m | Volumen de referencia de altura; no geometría de fabricación | Plano del fabricante: cargas de equipos; Plano del fabricante: implantación de equipos · referencia E7; Cimentaciones de equipos y pedestales del fabricante · revisión recibida 04/09/2026 | PPU-B-PLAN | 3.6311 | 3.6304 | 7.3 | 286.2 | 293.5 | 103.943 | 75.5186 | ["found_0904_c3bd5e0d38836a","found_0904_a16d8875227a01","found_0904_bc40ce234e571f"] | equipment | Equipos | yes | equipment_light_gray | Equipo · gris claro provisional | [0.88,0.89,0.88] | 0.45 | 0.28 | provisional | Referencia visual de fotografías públicas de Jinhong Gas / fabricante. Apariencia provisional para coordinación; fotografías oficiales pueden orientar el color, pero no acreditan el material, el acabado ni el equipo concreto. | Apoyo relativo +0.100 m; cero absoluto provisional | {"name":"No especificado","source":"Los contornos revisados no especifican el material del equipo.","status":"unknown"} | {"documented":[{"label":"Diámetro exterior ajustado al contorno CAD","value":3.630221,"unit":"m","source":"EQ-IMPLANTACION-20260430 · polilínea 9C27E","status":"derivado"},{"label":"Error radial máximo del ajuste","value":0.001255,"unit":"m","source":"EQ-IMPLANTACION-20260430 · polilínea 9C27E","status":"derivado"},{"label":"Número de huellas de apoyo","value":4,"unit":"ud","source":"EQ-IMPLANTACION-20260430 · 9C27F,9C280,9C281,9C282","status":"derivado"},{"label":"Cota relativa de la superficie de apoyo","value":0.1,"unit":"m","source":"LHD2609-JG00100-20260904 · sección 3 / 3-3 · 28D00, 28D41","status":"documentado"}],"geometry":[{"label":"Extensión de la malla en X","value":3.6310980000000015,"unit":"m","source":"Geometría releída del IFC; datum absoluto de proceso provisional","status":"derivado"},{"label":"Extensión de la malla en Y","value":3.6303999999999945,"unit":"m","source":"Geometría releída del IFC; datum absoluto de proceso provisional","status":"derivado"},{"label":"Extensión de la malla en Z","value":7.3,"unit":"m","source":"Geometría releída del IFC; datum absoluto de proceso provisional","status":"derivado"},{"label":"Cota inferior de visualización","value":286.2,"unit":"m","source":"Geometría releída del IFC; datum absoluto de proceso provisional","status":"derivado"},{"label":"Cota superior de visualización","value":293.5,"unit":"m","source":"Geometría releída del IFC; datum absoluto de proceso provisional","status":"derivado"}],"notes":["Geometría exterior de referencia; los volúmenes no representan cantidades de material, compra o fabricación."],"reference":[{"label":"Altura de referencia","value":7.3,"unit":"m","source":"SRC-MEETING-20260720-162843","status":"provisional"}]} | {"documentId":"EQ-IMPLANTACION-20260430","title":"Plano del fabricante: implantación de equipos · referencia E7","sheet":"Espacio modelo; referencia E7 en el nombre del archivo","date":"2026-04-30"} | {"Estado de la planta":"Derivado del CAD y del giro de implantación","Nivel relativo del apoyo (m)":0.1,"Estado del nivel relativo":"Documentado en el plano de cimentaciones","Cero absoluto de visualización (m)":286.1,"Estado del cero absoluto":"Provisional","Cota del apoyo de visualización (m)":286.20000000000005,"Desplazamiento aplicado a la malla (m)":0.10000000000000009,"Criterio":"Se conserva exactamente la base y posición XY publicadas; solo se sustituye la altura gráfica por una referencia atribuida. No se alteran las cimentaciones."} | ["Altura verbal de 7,30 m citada en la reunión del 20/07/2026 a las 16:28:43, aplicada provisionalmente a los dos adsorbedores. No es una cota confirmada de fabricante ni define la longitud de virola.","Envolvente de referencia obtenida al prolongar únicamente el contorno exterior del cuerpo CAD; las cuatro huellas de patas permanecen en el plano fuente. No se representan patas altas ni fondos curvos inventados.","Este volumen es conmutable por capa y no se utiliza como medición, gálibo certificado, capacidad ni definición de fabricación.","Cara superior de grout HA-35 de 50 mm a +0,100; hormigón a +0,050.","El cero absoluto de la revisión no está definido; 286,10 m sigue siendo una hipótesis de coordinación.","Se alinea el punto inferior del conjunto del equipo, incluidos los pies ya representados, con la superficie de apoyo terminada; no se añade un espesor de calzos, placa o grout del fabricante no documentado."] | {"boundingBoxM":{"min":[54.91688,53.944186,1.2],"max":[58.547978,57.574586,8.5]},"extentsM":[3.631098,3.6304,7.3],"meshSurfaceM2":103.943101,"meshVolumeM3":75.518581,"closedSolid":true,"basis":"Geometría de coordinación. Los volúmenes de referencia y subcomponentes no son cantidades de material ni componentes de fabricación certificados."} |  | {"documentId":"LHD2609-JG00100-20260904","title":"Cimentaciones y pedestales de equipos · revisión recibida 04/09/2026","date":"2026-09-04","sheet":"3 / 3-3","sourceHandles":["28D00","28D41"]} | referenceVolume | provisional | {"valueM":7.3,"status":"provisional","sourceRef":"SRC-MEETING-20260720-162843","baseModelZM":1.2,"baseAbsoluteVisualizationM":286.2,"fromFinishedFoundationSupport":true,"scope":"whole-equipment-envelope","sourceNote":"Altura verbal de 7,30 m citada en la reunión del 20/07/2026 a las 16:28:43, aplicada provisionalmente a los dos adsorbedores. No es una cota confirmada de fabricante ni define la longitud de virola.","sourcePlanObjectId":"SOURCE-PLAN-PPU-B-PLAN","sourcePlanGuid":"3GZenkddHKgwdrOvYSSQ6d"} | {"id":"equipment","name":"Equipos"} | {"profileId":"equipment_light_gray","name":"Equipo · gris claro provisional","materialName":"No especificado","physicalMaterialStatus":"unknown","physicalMaterialSource":"Los contornos revisados no especifican el material del equipo.","appearanceStatus":"provisional","appearanceBasis":"Referencia visual de fotografías públicas de Jinhong Gas / fabricante. Apariencia provisional para coordinación; fotografías oficiales pueden orientar el color, pero no acreditan el material, el acabado ni el equipo concreto.","note":"La apariencia gráfica no modifica ni confirma la especificación física del material."} | {"elementId":"PPU-B-PLAN","ifcGuid":"2wDdytY8bU5e9Eo4CEDi5M","ifcClass":"IfcBuildingElementProxy","buildingId":"process_plant","buildingName":"Planta de proceso","sourceDocumentId":"EQ-IMPLANTACION-20260430","sourceRepresentationKind":"planReference"} | {"layerId":"equipment","layerName":"Equipos","role":"Volumen de referencia de altura; no geometría de fabricación","basis":"Clasificación por función del elemento; no modifica las especificaciones documentales."} | {"profileId":"equipment_light_gray","name":"Equipo · gris claro provisional","status":"provisional","basis":"Referencia visual de fotografías públicas de Jinhong Gas / fabricante. Apariencia provisional para coordinación; fotografías oficiales pueden orientar el color, pero no acreditan el material, el acabado ni el equipo concreto.","physicalMaterialUnchanged":true} |  | Altura verbal de 7,30 m citada en la reunión del 20/07/2026 a las 16:28:43, aplicada provisionalmente a los dos adsorbedores. No es una cota confirmada de fabricante ni define la longitud de virola. Envolvente de referencia obtenida al prolongar únicamente el contorno exterior del cuerpo CAD; las cuatro huellas de patas permanecen en el plano fuente. No se representan patas altas ni fondos curvos inventados. |  | Plano del fabricante: implantación de equipos · referencia E7 | 9C27E, 9C27F, 9C280, 9C281, 9C282 |  |  |  | Metros en la plataforma local del fabricante; transformación de implantación aplicada durante la integración. |  | Referencia gráfica conmutable; no apta para medición, fabricación ni verificación certificada de interferencias. | Altura de referencia provisional | 0.1 | provisional | Geometría de coordinación. Los volúmenes de referencia y subcomponentes no son cantidades de material ni componentes de fabricación certificados. | Los contornos revisados no especifican el material del equipo. | Equipos; Zona de separación de aire; BIM · Equipos | JH_InformacionBIM - detailGeometry: {"source":{"documentId":"EQ-IMPLANTACION-20260430","title":"Plano del fabricante: implantación de equipos · referencia E7","sheet":"Espacio modelo; referencia E7 en el nombre del archivo","date":"2026-04-30"},"cadSource":"equipment_layout.dxf","conversion":"ODA","sourceInsertHandle":"8DD29","limitations":["La altura física del adsorbedor no está documentada; se conserva una referencia en planta de 0,10 m de espesor visual.","Se conserva cada vértice del contorno exterior CAD y las cuatro huellas de apoyo. El corte gráfico de la boquilla se cierra con una cuerda únicamente para cerrar la malla.","La circunferencia de ejes de 3,906 m corresponde a anclajes y no al diámetro exterior; queda excluida de la geometría de carcasa.","Las cotas verticales y la geometría de patas y boquillas requieren un alzado del fabricante."],"planMarkerThicknessM":0.1,"closureGapM":0.456618,"method":"Vertical extension of an existing closed source-plan component; identical XY and base Z.","sourceObjectId":"PPU-B-PLAN","sourceObjectGuid":"2wDdytY8bU5e9Eo4CEDi5M","sourceRefs":["SRC-V4-PUBLISHED-MODEL","SRC-EQUIPMENT-RECHECK","SRC-MEETING-20260720-162843"],"sourceVertexIndices":[0,1,2,3,4,5,6,7,8,9,10,11,12,13,14,15,16,17,18,19,20,21,22,23,24,25,26,27,28,29,30,31,32,33,34,35,36,37,38,39,40,41,42,43,44,45,46,47,48,49,50,51,52,53,54,55,56,57,58,59,60,61,62,63,64,65,66,67,68,69,70,71,72,73,74,75,76,77,78,79,80,81,82,83,84,85,86,87,88,89,90,91,92,93,94,95,96,97,98,99,100,101,102,103,104,105,106,107,108,109,110,111,112,113,114,115,116,117,118,119,120,121,122,123,124,125,126,127,128,129,130,131,132,133,134,135,136,137,138,139,140,141,142,143,144,145,146,147,148,149,150,151,152,153,154,155,156,157,158,159,160,161,162,163,164,165,166,167,168,169,170,171,172,173,174,175,176,177,178,179,180,181,182,183,184,185,186,187,188,189,190,191,192,193,194,195,196,197,198,199,200,201,202,203,204,205,206,207,208,209,210,211,212,213,214,215,216,217,218,219,220,221,222,223,224,225,226,227,228,229,230,231,232,233,234,235,236,237,238,239,240,241,242,243,244,245,246,247,248,249,250,251,252,253,254,255,256,257,258,259,260,261,262,263,264,265,266,267,268,269,270,271,272,273,274,275,276,277,278,279,280,281,282,283,284,285,286,287,288,289,290,291,292,293,294,295,296,297,298,299,300,301,302,303,304,305,306,307,308,309,310,311,312,313,314,315,316,317,318,319,320,321,322,323,324,325,326,327,328,329,330,331,332,333,334,335,336,337,338,339,340,341,342,343,344,345,346,347,348,349,350,351,352,353,354,355,356,357,358,359,360,361,362,363,364,365,366,367,368,369,370,371,372,373,374,375,376,377,378,379,380,381,382,383,384,385,386,387,388,389,390,391,392,393,394,395,396,397,398,399,400,401,402,403,404,405,406,407,408,409,410,411,412,413,414,415,416,417,418,419,420,421,422,423,424,425,426,427,428,429,430,431,432,433,434,435,436,437,438,439,440,441,442,443,444,445,446,447,448,449,450,451,452,453,454,455,456,457,458,459,460,461,462,463,464,465],"sourcePartCount":5,"heightReferenceM":7.3,"heightStatus":"provisional","planReferenceObjectId":"SOURCE-PLAN-PPU-B-PLAN","unconfirmedDimensions":["Actual equipment height and construction geometry remain unconfirmed."],"sourceGeometryClassification":"conceptual_envelope","partsAreBOM":false}; heightKind: oralReferenceEnvelope; physicalHeightConfirmed: no; quantityEligible: no; visualizationGeometryStatus: Volumen ilustrativo provisional; no sustituye cotas verificadas del fabricante.; JH_Trazabilidad - Altura de referencia (m): 7.3; Referencia de plano conservada: SOURCE-PLAN-PPU-B-PLAN; JH_DimensionesDocumentadas - Diámetro exterior ajustado al contorno CAD: 3.63022 m; Error radial máximo del ajuste: 0.001255 m; Número de huellas de apoyo: 4; JH_DetalleGeometrico - source: {"documentId":"EQ-IMPLANTACION-20260430","title":"Plano del fabricante: implantación de equipos · referencia E7","sheet":"Espacio modelo; referencia E7 en el nombre del archivo","date":"2026-04-30"}; cadSource: equipment_layout.dxf; conversion: ODA; sourceInsertHandle: 8DD29; limitations: ["La altura física del adsorbedor no está documentada; se conserva una referencia en planta de 0,10 m de espesor visual.","Se conserva cada vértice del contorno exterior CAD y las cuatro huellas de apoyo. El corte gráfico de la boquilla se cierra con una cuerda únicamente para cerrar la malla.","La circunferencia de ejes de 3,906 m corresponde a anclajes y no al diámetro exterior; queda excluida de la geometría de carcasa.","Las cotas verticales y la geometría de patas y boquillas requieren un alzado del fabricante."]; planMarkerThicknessM: 0.1; closureGapM: 0.456618; method: Vertical extension of an existing closed source-plan component; identical XY and base Z.; sourceObjectId: PPU-B-PLAN; sourceRefs: ["SRC-V4-PUBLISHED-MODEL","SRC-EQUIPMENT-RECHECK","SRC-MEETING-20260720-162843"]; sourceVertexIndices: [0,1,2,3,4,5,6,7,8,9,10,11,12,13,14,15,16,17,18,19,20,21,22,23,24,25,26,27,28,29,30,31,32,33,34,35,36,37,38,39,40,41,42,43,44,45,46,47,48,49,50,51,52,53,54,55,56,57,58,59,60,61,62,63,64,65,66,67,68,69,70,71,72,73,74,75,76,77,78,79,80,81,82,83,84,85,86,87,88,89,90,91,92,93,94,95,96,97,98,99,100,101,102,103,104,105,106,107,108,109,110,111,112,113,114,115,116,117,118,119,120,121,122,123,124,125,126,127,128,129,130,131,132,133,134,135,136,137,138,139,140,141,142,143,144,145,146,147,148,149,150,151,152,153,154,155,156,157,158,159,160,161,162,163,164,165,166,167,168,169,170,171,172,173,174,175,176,177,178,179,180,181,182,183,184,185,186,187,188,189,190,191,192,193,194,195,196,197,198,199,200,201,202,203,204,205,206,207,208,209,210,211,212,213,214,215,216,217,218,219,220,221,222,223,224,225,226,227,228,229,230,231,232,233,234,235,236,237,238,239,240,241,242,243,244,245,246,247,248,249,250,251,252,253,254,255,256,257,258,259,260,261,262,263,264,265,266,267,268,269,270,271,272,273,274,275,276,277,278,279,280,281,282,283,284,285,286,287,288,289,290,291,292,293,294,295,296,297,298,299,300,301,302,303,304,305,306,307,308,309,310,311,312,313,314,315,316,317,318,319,320,321,322,323,324,325,326,327,328,329,330,331,332,333,334,335,336,337,338,339,340,341,342,343,344,345,346,347,348,349,350,351,352,353,354,355,356,357,358,359,360,361,362,363,364,365,366,367,368,369,370,371,372,373,374,375,376,377,378,379,380,381,382,383,384,385,386,387,388,389,390,391,392,393,394,395,396,397,398,399,400,401,402,403,404,405,406,407,408,409,410,411,412,413,414,415,416,417,418,419,420,421,422,423,424,425,426,427,428,429,430,431,432,433,434,435,436,437,438,439,440,441,442,443,444,445,446,447,448,449,450,451,452,453,454,455,456,457,458,459,460,461,462,463,464,465]; sourcePartCount: 5; heightReferenceM: 7.3; heightStatus: provisional; planReferenceObjectId: SOURCE-PLAN-PPU-B-PLAN; unconfirmedDimensions: ["Actual equipment height and construction geometry remain unconfirmed."]; sourceGeometryClassification: conceptual_envelope; partsAreBOM: no
Bombas y dosificación · envolvente máxima H ≤ 2,00 m | Volumen de referencia de altura; no geometría de fabricación | Plano del fabricante: cargas de equipos; Cimentaciones de equipos y pedestales del fabricante · revisión recibida 04/09/2026 | PUMPS-DOSING-PLAN | 6.07843 | 2.14783 | 2 | 286.3 | 288.3 | 45.265 | 16.065 | ["found_0904_9fc68ac0a59c86","found_0904_931d97c2f216a1","found_0904_b8078a859dac4b"] | equipment | Equipos | yes | equipment_light_gray | Equipo · gris claro provisional | [0.88,0.89,0.88] | 0.45 | 0.28 | provisional | Referencia visual de fotografías públicas de Jinhong Gas / fabricante. Apariencia provisional para coordinación; fotografías oficiales pueden orientar el color, pero no acreditan el material, el acabado ni el equipo concreto. | Apoyo relativo +0.200 m; cero absoluto provisional | {"name":"No especificado","source":"Sin especificación de material en la documentación revisada","status":"unknown"} | {"documented":[{"label":"Dimensión X local del grupo","value":5.95,"unit":"m","source":"EQ-CARGAS-20260825 · contorno 260E","status":"derivado"},{"label":"Dimensión Y local del grupo","value":1.35,"unit":"m","source":"EQ-CARGAS-20260825 · contorno 260E","status":"derivado"},{"label":"Límite superior de altura, no altura física confirmada","value":2,"unit":"m","source":"EQ-CARGAS-20260825 · indicación ≤ 2 m · handle 260A","status":"documentado"},{"label":"Cota relativa de la superficie de apoyo","value":0.2,"unit":"m","source":"LHD2609-JG00100-20260904 · sección 10–12 / 10-10 · 2484F, 24886","status":"documentado"}],"geometry":[{"label":"Extensión de la malla en X","value":6.078426,"unit":"m","source":"Geometría releída del IFC; datum absoluto de proceso provisional","status":"derivado"},{"label":"Extensión de la malla en Y","value":2.147832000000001,"unit":"m","source":"Geometría releída del IFC; datum absoluto de proceso provisional","status":"derivado"},{"label":"Extensión de la malla en Z","value":1.9999999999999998,"unit":"m","source":"Geometría releída del IFC; datum absoluto de proceso provisional","status":"derivado"},{"label":"Cota inferior de visualización","value":286.3,"unit":"m","source":"Geometría releída del IFC; datum absoluto de proceso provisional","status":"derivado"},{"label":"Cota superior de visualización","value":288.3,"unit":"m","source":"Geometría releída del IFC; datum absoluto de proceso provisional","status":"derivado"}],"notes":["Las extensiones de la malla se miden en los ejes del proyecto tras el giro de implantación; no sustituyen las dimensiones locales del fabricante.","La envolvente, su volumen y los espesores de visualización no son volúmenes de material ni cantidades de compra, construcción o fabricación.","Las dimensiones documentadas distinguen cotas explícitas y medidas extraídas de contornos CAD; las dimensiones geométricas describen únicamente la malla publicada."],"reference":[{"label":"Límite superior de altura representado","value":2.0,"unit":"m","source":"SRC-LOAD-20260825-260A","status":"documented_upper_bound"}]} | {"documentId":"EQ-CARGAS-20260825","title":"Plano del fabricante: cargas de equipos","sheet":"Espacio modelo; número de plano no identificado","date":"2026-08-25"} | {"Estado de la planta":"Derivado del CAD y del giro de implantación","Nivel relativo del apoyo (m)":0.2,"Estado del nivel relativo":"Documentado en el plano de cimentaciones","Cero absoluto de visualización (m)":286.1,"Estado del cero absoluto":"Provisional","Cota del apoyo de visualización (m)":286.3,"Desplazamiento aplicado a la malla (m)":0.2000000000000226,"Criterio":"Se conserva exactamente la base y posición XY publicadas; solo se sustituye la altura gráfica por una referencia atribuida. No se alteran las cimentaciones."} | ["La anotación del fabricante indica ≤ 2 m. El volumen representa el máximo de altura desde el plano de apoyo; la altura física sigue sin confirmarse.","Volumen de límite superior del grupo completo; no representa la forma física de bombas, dosificación, bancada ni armarios.","Este volumen es conmutable por capa y no se utiliza como medición, gálibo certificado, capacidad ni definición de fabricación.","El cuadro agrupa equipos 10–12 sobre un único skid; confirmar identidad del conjunto de bombas por su posición final.","El cero absoluto de la revisión no está definido; 286,10 m sigue siendo una hipótesis de coordinación.","Se alinea el punto inferior del conjunto del equipo, incluidos los pies ya representados, con la superficie de apoyo terminada; no se añade un espesor de calzos, placa o grout del fabricante no documentado."] | {"boundingBoxM":{"min":[36.575699,55.725405,1.3],"max":[42.654125,57.873237,3.3]},"extentsM":[6.078426,2.147832,2.0],"meshSurfaceM2":45.264998,"meshVolumeM3":16.064998,"closedSolid":true,"basis":"Geometría de coordinación. Los volúmenes de referencia y subcomponentes no son cantidades de material ni componentes de fabricación certificados."} | {"material":false,"document":true,"quantities":true,"containerGuid":"17utmjd_LKsAVvPyuSUhFt","containerName":"Parcela industrial Jinhong"} | {"documentId":"LHD2609-JG00100-20260904","title":"Cimentaciones y pedestales de equipos · revisión recibida 04/09/2026","date":"2026-09-04","sheet":"10–12 / 10-10","sourceHandles":["2484F","24886"]} | referenceVolume | documented_upper_bound | {"valueM":2.0,"status":"documented_upper_bound","sourceRef":"SRC-LOAD-20260825-260A","baseModelZM":1.3,"baseAbsoluteVisualizationM":286.3,"fromFinishedFoundationSupport":true,"scope":"maximum-group-envelope","sourceNote":"La anotación del fabricante indica ≤ 2 m. El volumen representa el máximo de altura desde el plano de apoyo; la altura física sigue sin confirmarse.","sourcePlanObjectId":"SOURCE-PLAN-PUMPS-DOSING-PLAN","sourcePlanGuid":"2Tq61AsZDItRZM3BO4BNMd"} | {"id":"equipment","name":"Equipos"} | {"profileId":"equipment_light_gray","name":"Equipo · gris claro provisional","materialName":"No especificado","physicalMaterialStatus":"unknown","physicalMaterialSource":"Sin especificación de material en la documentación revisada","appearanceStatus":"provisional","appearanceBasis":"Referencia visual de fotografías públicas de Jinhong Gas / fabricante. Apariencia provisional para coordinación; fotografías oficiales pueden orientar el color, pero no acreditan el material, el acabado ni el equipo concreto.","note":"La apariencia gráfica no modifica ni confirma la especificación física del material."} | {"elementId":"PUMPS-DOSING-PLAN","ifcGuid":"3bYFGHJXrP091wOaX29ECq","ifcClass":"IfcBuildingElementProxy","buildingId":"process_plant","buildingName":"Planta de proceso","sourceDocumentId":"EQ-CARGAS-20260825","sourceRepresentationKind":"planReference"} | {"layerId":"equipment","layerName":"Equipos","role":"Volumen de referencia de altura; no geometría de fabricación","basis":"Clasificación por función del elemento; no modifica las especificaciones documentales."} | {"profileId":"equipment_light_gray","name":"Equipo · gris claro provisional","status":"provisional","basis":"Referencia visual de fotografías públicas de Jinhong Gas / fabricante. Apariencia provisional para coordinación; fotografías oficiales pueden orientar el color, pero no acreditan el material, el acabado ni el equipo concreto.","physicalMaterialUnchanged":true} | 10/11/12 | La anotación del fabricante indica ≤ 2 m. El volumen representa el máximo de altura desde el plano de apoyo; la altura física sigue sin confirmarse. Volumen de límite superior del grupo completo; no representa la forma física de bombas, dosificación, bancada ni armarios. | Nivel de apoyo relativo documentado. Se adopta el cero de proceso a 286,10 m solo para visualización; la equivalencia absoluta no está confirmada. No se añade un espesor de montaje sin cota del fabricante. | Plano del fabricante: cargas de equipos · 2026-08-25 · Espacio modelo; número de plano no identificado | 260E | Contorno del fabricante de 5,95 × 1,35 m. La indicación de altura ≤ 2 m es únicamente un límite superior; no permite asignar la altura real de los cuerpos de las bombas. | 27 × 57 m; dimensiones acotadas en el plano general. | El punto de referencia del fabricante coincide con la esquina suroeste de la zona de equipos. Giro local de −7,82824° para la implantación en coordenadas UTM. | Coordenadas locales del proyecto en metros. Añadir (729400, 4301550, 285) para recuperar las coordenadas UTM y las cotas del plano. | Sólido IFC4 mediante malla triangular cerrada | Referencia gráfica conmutable; no apta para medición, fabricación ni verificación certificada de interferencias. | Envolvente máxima; altura física desconocida | 0.2 | documented_upper_bound | Geometría de coordinación. Los volúmenes de referencia y subcomponentes no son cantidades de material ni componentes de fabricación certificados. | Sin especificación de material en la documentación revisada | Equipos; Zona de separación de aire; BIM · Equipos | JH_InformacionBIM - detailGeometry: {"method":"Vertical extension of an existing closed source-plan component; identical XY and base Z.","sourceObjectId":"PUMPS-DOSING-PLAN","sourceObjectGuid":"3bYFGHJXrP091wOaX29ECq","sourceRefs":["SRC-V4-PUBLISHED-MODEL","SRC-EQUIPMENT-RECHECK","SRC-LOAD-20260825-260A"],"sourceVertexIndices":[0,1,2,3,4,5,6,7],"sourcePartCount":1,"heightReferenceM":2.0,"heightStatus":"documented_upper_bound","planReferenceObjectId":"SOURCE-PLAN-PUMPS-DOSING-PLAN","unconfirmedDimensions":["Actual individual pump/dosing heights and internal component arrangement remain unconfirmed."],"sourceGeometryClassification":"conceptual_envelope","partsAreBOM":false}; heightKind: maximumEnvelope; physicalHeightConfirmed: no; quantityEligible: no; visualizationGeometryStatus: Volumen ilustrativo provisional; no sustituye cotas verificadas del fabricante.; JH_Trazabilidad - Altura de referencia (m): 2; Referencia de plano conservada: SOURCE-PLAN-PUMPS-DOSING-PLAN; Capa CAD de referencia: Anotaciones y contornos de equipos; Identificador CAD de la cota de altura (handle): 260A; Límite superior de altura indicado (m): 2; JH_DetalleGeometrico - method: Vertical extension of an existing closed source-plan component; identical XY and base Z.; sourceObjectId: PUMPS-DOSING-PLAN; sourceRefs: ["SRC-V4-PUBLISHED-MODEL","SRC-EQUIPMENT-RECHECK","SRC-LOAD-20260825-260A"]; sourceVertexIndices: [0,1,2,3,4,5,6,7]; sourcePartCount: 1; heightReferenceM: 2; heightStatus: documented_upper_bound; planReferenceObjectId: SOURCE-PLAN-PUMPS-DOSING-PLAN; unconfirmedDimensions: ["Actual individual pump/dosing heights and internal component arrangement remain unconfirmed."]; sourceGeometryClassification: conceptual_envelope; partsAreBOM: no; JH_DimensionesDocumentadas - Dimensión X local del grupo: 5.95 m; Dimensión Y local del grupo: 1.35 m; Límite superior de altura, no altura física confirmada: 2 m

# IfcColumn (10)
In: Planta baja
Description: Pilar; PredefinedType: COLUMN; Material: Acero estructural S355JR; Group: Estructura; BIM · Estructura
JH_InformacionBIM - level: Planta baja; category: Pilar; ifcClass: IfcColumn; status: provisional; visualLayer: {"id":"structure","name":"Estructura"}; componentSeparation: {"status":"objeto_independiente","note":"Control de visibilidad del objeto completo; la clasificación no altera la malla."}; classification: {"layerId":"structure","layerName":"Estructura","role":"Pilar","basis":"Clasificación por función del elemento; no modifica las especificaciones documentales."}; layerId: structure; appearance: {"profileId":"steel_structural","name":"Acero estructural · protección gris","status":"criterio_visual","basis":"S355JR consta en la documentación; protección superficial gris adoptada para visualización, sin especificación de pintura confirmada.","physicalMaterialUnchanged":true}
JH_Trazabilidad - Base geométrica: Dimensiones nominales del perfil verificadas en el catálogo; acuerdos sustituidos por aristas rectas.; Sistema de coordenadas: Coordenadas de proyecto en metros; sumar (729400, 4301550, 285) para recuperar las coordenadas UTM y cotas de los planos.; Uso del modelo: Reconstrucción tridimensional de la documentación y revisión preliminar de coordinación; pendiente de revisión por el equipo de diseño.; Acero: S355JR; Catálogo del perfil: https://sections.arcelormittal.com/repository2/Sections/5_1_5_ArcelorMittal_FR_EN_RU_web.pdf; Página PDF del catálogo: 84; Simplificación del arranque: Uniones de pie de pilar no modeladas; arranque deducido de la cota de zapata o del detalle de placa de base disponible.; Verificación de la malla: Malla cerrada, orientación coherente de las caras y volumen positivo.; Referencia de implantación: Plano general U004 de 2026-07-31; geometría vectorial del PDF registrada con las coordenadas de lindero indicadas.; Disciplina: Estructura; Clase IFC: IfcColumn; Fase del modelo: V0.1 · Reconstrucción documental y coordinación preliminar; Representación geométrica: Sólido de malla triangular cerrada en IFC4; Aplicabilidad de las mediciones: Volumen exclusivamente geométrico; los espesores de representación, las simplificaciones y las envolventes no constituyen mediciones de compra, ejecución, fabricación ni volumen neto de material.; Material: Acero estructural S355JR; Capa BIM: Estructura; Acabado de visualización: Acero estructural · protección gris; Estado del acabado: criterio_visual; Categoria: Pilar; ClaseIFC: IfcColumn; EstadoDeInformacion: provisional; UsoDeLasMagnitudes: Geometría de coordinación. Los volúmenes de referencia y subcomponentes no son cantidades de material ni componentes de fabricación certificados.
JH_EvidenciaDeMaterial - name: Acero estructural S355JR; status: known
JH_DimensionesDocumentadas - Anchura nominal de ala: 300; Espesor nominal de alma: 11; Espesor nominal de ala: 19
JH_CapaBIM - IdentificadorCapa: structure; NombreCapa: Estructura; Funcion: Pilar; VisibilidadInicial: yes
JH_AcabadoVisual - Perfil: steel_structural; Acabado: Acero estructural · protección gris; ColorRGB: [0.396078,0.454902,0.482353]; Rugosidad: 0.52; Metallicidad: 0.35; Estado: criterio_visual; Referencia: S355JR consta en la documentación; protección superficial gris adoptada para visualización, sin especificación de pintura confirmada.; Nota: La apariencia no certifica el material físico ni el acabado de fabricación.
Name | Document | Dimensiones de la caja local del elemento (X, Y, Z) | Cota mínima absoluta de la malla (m) | Cota máxima absoluta de la malla (m) | Volumen geométrico bruto (m3) = Volumen geométrico (m³) | Reference = Identificador del elemento = Identificador | ExtensionX (m) | ExtensionY (m) | ExtensionZ (m) | SuperficieDeLaMalla (m2) | VolumenGeometrico (m3) = GrossVolume (m3) | buildingId | buildingName = Edificio | material | dimensions | JH_InformacionBIM, source = DocumentoFuente | issues = IncidenciasPendientes | positioning = PosicionYEstado | geometryMetrics | ifcAssociations | materialAppearance | visualizationIdentity | Planos de referencia = Referencia del material = JH_EvidenciaDeMaterial, source | Perfil laminado = Perfil | Dimensiones nominales del perfil (mm) | Coordinación de cotas pendiente | Estado de la implantación | Cota de planta baja terminada (m) | Canto nominal del perfil | Discrepancia entre versiones
Sala de bombas contra incendios · pilar HEB300 · 1 | Planos de estructura de la sala de bombas contra incendios; Planos de estructura de la sala de bombas contra incendios | 0.3 × 0.3 × 6.41 | 284.84 | 291.25 | 0.091548 | pump_house_0048 | 0.338065 | 0.338065 | 6.41 | 11.4255 | 0.0915468 | pump_house | Sala de bombas contra incendios | {"name":"Acero estructural S355JR","source":"EST-SB-20260710 · Estructura A101 / p. 2, A402 / p. 9","status":"known"} | {"documented":[{"label":"Perfil","value":"HEB300","unit":"designación","source":"EST-SB-20260710 · Estructura A101 / p. 2, A402 / p. 9","status":"documentado"},{"label":"Canto nominal del perfil","value":300,"unit":"mm","source":"Catálogo de perfiles ArcelorMittal · 84","status":"documentado"},{"label":"Anchura nominal de ala","value":300,"unit":"mm","source":"Catálogo de perfiles ArcelorMittal · 84","status":"documentado"},{"label":"Espesor nominal de alma","value":11,"unit":"mm","source":"Catálogo de perfiles ArcelorMittal · 84","status":"documentado"},{"label":"Espesor nominal de ala","value":19,"unit":"mm","source":"Catálogo de perfiles ArcelorMittal · 84","status":"documentado"}],"geometry":[{"label":"Dimensiones de la caja local del elemento (X, Y, Z)","value":"0.3 × 0.3 × 6.41","unit":"m","source":"Malla triangulada del elemento en ejes locales del edificio","status":"derivado"},{"label":"Cota mínima absoluta de la malla","value":284.84,"unit":"m","source":"Malla de proyecto y origen altimétrico 285 m","status":"derivado"},{"label":"Cota máxima absoluta de la malla","value":291.25,"unit":"m","source":"Malla de proyecto y origen altimétrico 285 m","status":"derivado"},{"label":"Volumen geométrico bruto","value":0.091548,"unit":"m³","source":"Malla cerrada del elemento","status":"derivado"}],"notes":["Las dimensiones documentadas proceden de anotaciones o cuadros; la caja y el volumen se calculan a partir de la malla.","El volumen es exclusivamente geométrico y bruto; no representa una medición neta de material ni una cantidad de compra."]} | {"documentId":"EST-SB-20260710","title":"Planos de estructura de la sala de bombas contra incendios","date":"2026-07-10","sheet":"Estructura A101 / p. 2, A402 / p. 9"} | ["Cabeza de pilar: +5,00 m en el eje A y +4,60 m en el eje B.","Uniones de pie de pilar no modeladas; arranque deducido de la cota de zapata o del detalle de placa de base disponible.","Registro de líneas del PDF general con envolvente de 10,2 × 8,2 m. Estimación de trabajo de implantación de ±0,15 m, pendiente de CAD nativo; no constituye una precisión topográfica garantizada."] | {"horizontalStatus":"derivado","verticalStatus":"provisional","baseElevationM":286.25,"note":"Registro de líneas del PDF general con envolvente de 10,2 × 8,2 m. Estimación de trabajo de implantación de ±0,15 m, pendiente de CAD nativo; no constituye una precisión topográfica garantizada."} | {"boundingBoxM":{"min":[8.341469,26.923883,-0.16],"max":[8.679534,27.261948,6.25]},"extentsM":[0.338065,0.338065,6.41],"meshSurfaceM2":11.425547,"meshVolumeM3":0.091547,"closedSolid":true,"basis":"Geometría triangulada releída del IFC; envolventes y magnitudes no contractuales."} | {"material":true,"document":true,"quantities":true,"containerGuid":"0Wh59pm9LO_einrwiq6Es1","containerName":"Planta baja"} | {"profileId":"steel_structural","name":"Acero estructural · protección gris","materialName":"Acero estructural S355JR","physicalMaterialStatus":"known","physicalMaterialSource":"EST-SB-20260710 · Estructura A101 / p. 2, A402 / p. 9","appearanceStatus":"criterio_visual","appearanceBasis":"S355JR consta en la documentación; protección superficial gris adoptada para visualización, sin especificación de pintura confirmada.","note":"La apariencia gráfica no modifica ni confirma la especificación física del material."} | {"elementId":"pump_house_0048","ifcGuid":"206do050fM_BHIFRl7Fj1i","ifcClass":"IfcColumn","buildingId":"pump_house","buildingName":"Sala de bombas contra incendios","sourceDocumentId":"EST-SB-20260710","sourceRepresentationKind":"documentary_mesh"} | EST-SB-20260710 · Estructura A101 / p. 2, A402 / p. 9 | HEB300 | {"h":300.0,"b":300.0,"tw":11.0,"tf":19.0} | Cabeza de pilar: +5,00 m en el eje A y +4,60 m en el eje B. | Registro de líneas del PDF general con envolvente de 10,2 × 8,2 m. Estimación de trabajo de implantación de ±0,15 m, pendiente de CAD nativo; no constituye una precisión topográfica garantizada. | 286.25 | 300
Sala de bombas contra incendios · pilar HEB300 · 2 | Planos de estructura de la sala de bombas contra incendios; Planos de estructura de la sala de bombas contra incendios | 0.3 × 0.3 × 6.41 | 284.84 | 291.25 | 0.091548 | pump_house_0049 | 0.338066 | 0.338065 | 6.41 | 11.4255 | 0.0915471 | pump_house | Sala de bombas contra incendios | {"name":"Acero estructural S355JR","source":"EST-SB-20260710 · Estructura A101 / p. 2, A402 / p. 9","status":"known"} | {"documented":[{"label":"Perfil","value":"HEB300","unit":"designación","source":"EST-SB-20260710 · Estructura A101 / p. 2, A402 / p. 9","status":"documentado"},{"label":"Canto nominal del perfil","value":300,"unit":"mm","source":"Catálogo de perfiles ArcelorMittal · 84","status":"documentado"},{"label":"Anchura nominal de ala","value":300,"unit":"mm","source":"Catálogo de perfiles ArcelorMittal · 84","status":"documentado"},{"label":"Espesor nominal de alma","value":11,"unit":"mm","source":"Catálogo de perfiles ArcelorMittal · 84","status":"documentado"},{"label":"Espesor nominal de ala","value":19,"unit":"mm","source":"Catálogo de perfiles ArcelorMittal · 84","status":"documentado"}],"geometry":[{"label":"Dimensiones de la caja local del elemento (X, Y, Z)","value":"0.3 × 0.3 × 6.41","unit":"m","source":"Malla triangulada del elemento en ejes locales del edificio","status":"derivado"},{"label":"Cota mínima absoluta de la malla","value":284.84,"unit":"m","source":"Malla de proyecto y origen altimétrico 285 m","status":"derivado"},{"label":"Cota máxima absoluta de la malla","value":291.25,"unit":"m","source":"Malla de proyecto y origen altimétrico 285 m","status":"derivado"},{"label":"Volumen geométrico bruto","value":0.091548,"unit":"m³","source":"Malla cerrada del elemento","status":"derivado"}],"notes":["Las dimensiones documentadas proceden de anotaciones o cuadros; la caja y el volumen se calculan a partir de la malla.","El volumen es exclusivamente geométrico y bruto; no representa una medición neta de material ni una cantidad de compra."]} | {"documentId":"EST-SB-20260710","title":"Planos de estructura de la sala de bombas contra incendios","date":"2026-07-10","sheet":"Estructura A101 / p. 2, A402 / p. 9"} | ["Cabeza de pilar: +5,00 m en el eje A y +4,60 m en el eje B.","Uniones de pie de pilar no modeladas; arranque deducido de la cota de zapata o del detalle de placa de base disponible.","Registro de líneas del PDF general con envolvente de 10,2 × 8,2 m. Estimación de trabajo de implantación de ±0,15 m, pendiente de CAD nativo; no constituye una precisión topográfica garantizada."] | {"horizontalStatus":"derivado","verticalStatus":"provisional","baseElevationM":286.25,"note":"Registro de líneas del PDF general con envolvente de 10,2 × 8,2 m. Estimación de trabajo de implantación de ±0,15 m, pendiente de CAD nativo; no constituye una precisión topográfica garantizada."} | {"boundingBoxM":{"min":[17.752936,25.629946,-0.16],"max":[18.091002,25.968011,6.25]},"extentsM":[0.338066,0.338065,6.41],"meshSurfaceM2":11.425547,"meshVolumeM3":0.091547,"closedSolid":true,"basis":"Geometría triangulada releída del IFC; envolventes y magnitudes no contractuales."} | {"material":true,"document":true,"quantities":true,"containerGuid":"0Wh59pm9LO_einrwiq6Es1","containerName":"Planta baja"} | {"profileId":"steel_structural","name":"Acero estructural · protección gris","materialName":"Acero estructural S355JR","physicalMaterialStatus":"known","physicalMaterialSource":"EST-SB-20260710 · Estructura A101 / p. 2, A402 / p. 9","appearanceStatus":"criterio_visual","appearanceBasis":"S355JR consta en la documentación; protección superficial gris adoptada para visualización, sin especificación de pintura confirmada.","note":"La apariencia gráfica no modifica ni confirma la especificación física del material."} | {"elementId":"pump_house_0049","ifcGuid":"1zZ5ytTJzKkucaOEylw8el","ifcClass":"IfcColumn","buildingId":"pump_house","buildingName":"Sala de bombas contra incendios","sourceDocumentId":"EST-SB-20260710","sourceRepresentationKind":"documentary_mesh"} | EST-SB-20260710 · Estructura A101 / p. 2, A402 / p. 9 | HEB300 | {"h":300.0,"b":300.0,"tw":11.0,"tf":19.0} | Cabeza de pilar: +5,00 m en el eje A y +4,60 m en el eje B. | Registro de líneas del PDF general con envolvente de 10,2 × 8,2 m. Estimación de trabajo de implantación de ±0,15 m, pendiente de CAD nativo; no constituye una precisión topográfica garantizada. | 286.25 | 300
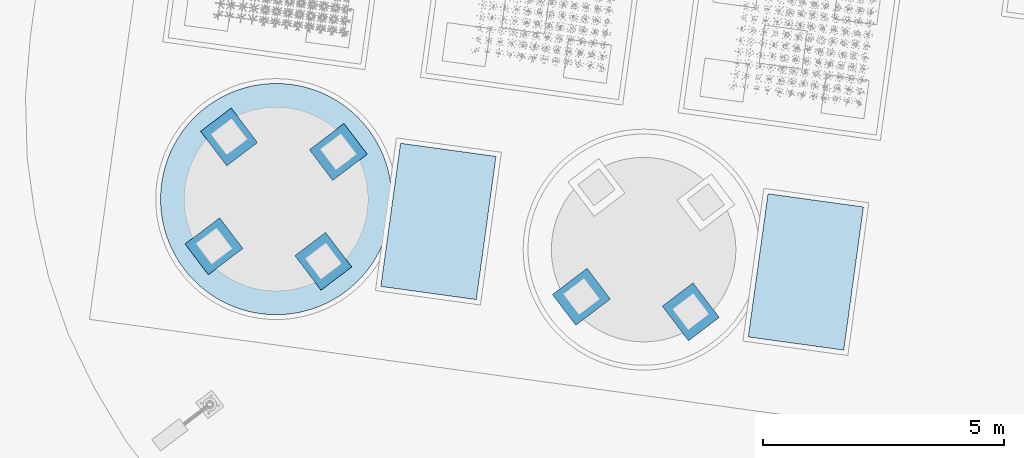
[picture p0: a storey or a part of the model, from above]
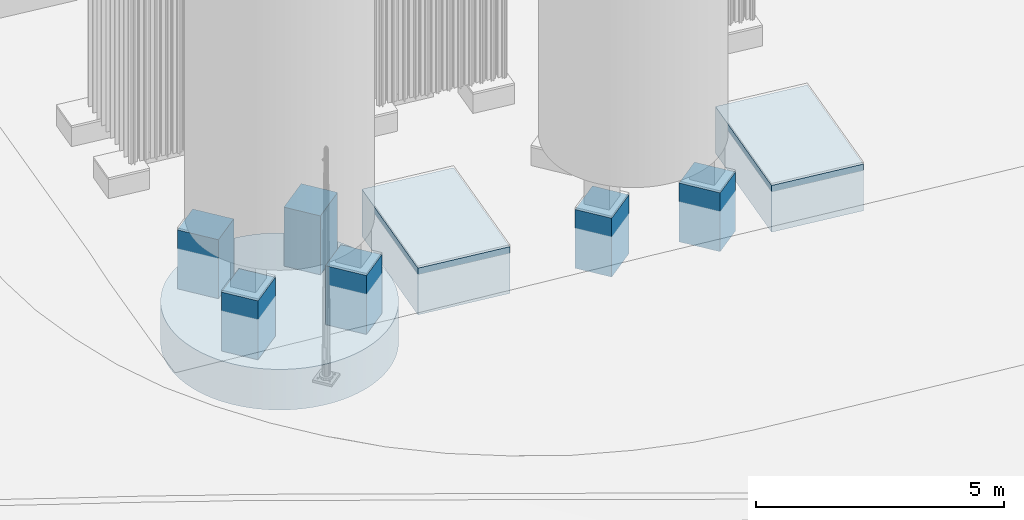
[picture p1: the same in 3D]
Properties of the parts of a building model (IFC4), part 56 of 134

# IfcColumn (10)
Name | Document | Dimensiones de la caja local del elemento (X, Y, Z) | Cota mínima absoluta de la malla (m) | Cota máxima absoluta de la malla (m) | Volumen geométrico bruto (m3) = Volumen geométrico (m³) | Reference = Identificador del elemento = Identificador | ExtensionX (m) | ExtensionY (m) | ExtensionZ (m) | SuperficieDeLaMalla (m2) | VolumenGeometrico (m3) = GrossVolume (m3) | buildingId | buildingName = Edificio | material | dimensions | JH_InformacionBIM, source = DocumentoFuente | issues = IncidenciasPendientes | positioning = PosicionYEstado | geometryMetrics | ifcAssociations | materialAppearance | visualizationIdentity | Planos de referencia = Referencia del material = JH_EvidenciaDeMaterial, source | Perfil laminado = Perfil | Dimensiones nominales del perfil (mm) | Coordinación de cotas pendiente | Estado de la implantación | Cota de planta baja terminada (m) | Canto nominal del perfil | Discrepancia entre versiones
Sala de bombas contra incendios · pilar HEB300 · 3 | Planos de estructura de la sala de bombas contra incendios; Planos de estructura de la sala de bombas contra incendios | 0.3 × 0.3 × 6.01 | 284.84 | 290.85 | 0.085835 | pump_house_0050 | 0.338066 | 0.338065 | 6.01 | 10.7143 | 0.0858344 | pump_house | Sala de bombas contra incendios | {"name":"Acero estructural S355JR","source":"EST-SB-20260710 · Estructura A101 / p. 2, A402 / p. 9","status":"known"} | {"documented":[{"label":"Perfil","value":"HEB300","unit":"designación","source":"EST-SB-20260710 · Estructura A101 / p. 2, A402 / p. 9","status":"documentado"},{"label":"Canto nominal del perfil","value":300,"unit":"mm","source":"Catálogo de perfiles ArcelorMittal · 84","status":"documentado"},{"label":"Anchura nominal de ala","value":300,"unit":"mm","source":"Catálogo de perfiles ArcelorMittal · 84","status":"documentado"},{"label":"Espesor nominal de alma","value":11,"unit":"mm","source":"Catálogo de perfiles ArcelorMittal · 84","status":"documentado"},{"label":"Espesor nominal de ala","value":19,"unit":"mm","source":"Catálogo de perfiles ArcelorMittal · 84","status":"documentado"}],"geometry":[{"label":"Dimensiones de la caja local del elemento (X, Y, Z)","value":"0.3 × 0.3 × 6.01","unit":"m","source":"Malla triangulada del elemento en ejes locales del edificio","status":"derivado"},{"label":"Cota mínima absoluta de la malla","value":284.84,"unit":"m","source":"Malla de proyecto y origen altimétrico 285 m","status":"derivado"},{"label":"Cota máxima absoluta de la malla","value":290.85,"unit":"m","source":"Malla de proyecto y origen altimétrico 285 m","status":"derivado"},{"label":"Volumen geométrico bruto","value":0.085835,"unit":"m³","source":"Malla cerrada del elemento","status":"derivado"}],"notes":["Las dimensiones documentadas proceden de anotaciones o cuadros; la caja y el volumen se calculan a partir de la malla.","El volumen es exclusivamente geométrico y bruto; no representa una medición neta de material ni una cantidad de compra."]} | {"documentId":"EST-SB-20260710","title":"Planos de estructura de la sala de bombas contra incendios","date":"2026-07-10","sheet":"Estructura A101 / p. 2, A402 / p. 9"} | ["Cabeza de pilar: +5,00 m en el eje A y +4,60 m en el eje B.","Uniones de pie de pilar no modeladas; arranque deducido de la cota de zapata o del detalle de placa de base disponible.","Registro de líneas del PDF general con envolvente de 10,2 × 8,2 m. Estimación de trabajo de implantación de ±0,15 m, pendiente de CAD nativo; no constituye una precisión topográfica garantizada."] | {"horizontalStatus":"derivado","verticalStatus":"provisional","baseElevationM":286.25,"note":"Registro de líneas del PDF general con envolvente de 10,2 × 8,2 m. Estimación de trabajo de implantación de ±0,15 m, pendiente de CAD nativo; no constituye una precisión topográfica garantizada."} | {"boundingBoxM":{"min":[9.362998,34.353989,-0.16],"max":[9.701064,34.692054,5.85]},"extentsM":[0.338066,0.338065,6.01],"meshSurfaceM2":10.714347,"meshVolumeM3":0.085834,"closedSolid":true,"basis":"Geometría triangulada releída del IFC; envolventes y magnitudes no contractuales."} | {"material":true,"document":true,"quantities":true,"containerGuid":"0Wh59pm9LO_einrwiq6Es1","containerName":"Planta baja"} | {"profileId":"steel_structural","name":"Acero estructural · protección gris","materialName":"Acero estructural S355JR","physicalMaterialStatus":"known","physicalMaterialSource":"EST-SB-20260710 · Estructura A101 / p. 2, A402 / p. 9","appearanceStatus":"criterio_visual","appearanceBasis":"S355JR consta en la documentación; protección superficial gris adoptada para visualización, sin especificación de pintura confirmada.","note":"La apariencia gráfica no modifica ni confirma la especificación física del material."} | {"elementId":"pump_house_0050","ifcGuid":"03UFr_RzbIRehP5b4RIc0s","ifcClass":"IfcColumn","buildingId":"pump_house","buildingName":"Sala de bombas contra incendios","sourceDocumentId":"EST-SB-20260710","sourceRepresentationKind":"documentary_mesh"} | EST-SB-20260710 · Estructura A101 / p. 2, A402 / p. 9 | HEB300 | {"h":300.0,"b":300.0,"tw":11.0,"tf":19.0} | Cabeza de pilar: +5,00 m en el eje A y +4,60 m en el eje B. | Registro de líneas del PDF general con envolvente de 10,2 × 8,2 m. Estimación de trabajo de implantación de ±0,15 m, pendiente de CAD nativo; no constituye una precisión topográfica garantizada. | 286.25 | 300
Sala de bombas contra incendios · pilar HEB300 · 4 | Planos de estructura de la sala de bombas contra incendios; Planos de estructura de la sala de bombas contra incendios | 0.3 × 0.3 × 6.01 | 284.84 | 290.85 | 0.085835 | pump_house_0051 | 0.338065 | 0.338065 | 6.01 | 10.7143 | 0.0858341 | pump_house | Sala de bombas contra incendios | {"name":"Acero estructural S355JR","source":"EST-SB-20260710 · Estructura A101 / p. 2, A402 / p. 9","status":"known"} | {"documented":[{"label":"Perfil","value":"HEB300","unit":"designación","source":"EST-SB-20260710 · Estructura A101 / p. 2, A402 / p. 9","status":"documentado"},{"label":"Canto nominal del perfil","value":300,"unit":"mm","source":"Catálogo de perfiles ArcelorMittal · 84","status":"documentado"},{"label":"Anchura nominal de ala","value":300,"unit":"mm","source":"Catálogo de perfiles ArcelorMittal · 84","status":"documentado"},{"label":"Espesor nominal de alma","value":11,"unit":"mm","source":"Catálogo de perfiles ArcelorMittal · 84","status":"documentado"},{"label":"Espesor nominal de ala","value":19,"unit":"mm","source":"Catálogo de perfiles ArcelorMittal · 84","status":"documentado"}],"geometry":[{"label":"Dimensiones de la caja local del elemento (X, Y, Z)","value":"0.3 × 0.3 × 6.01","unit":"m","source":"Malla triangulada del elemento en ejes locales del edificio","status":"derivado"},{"label":"Cota mínima absoluta de la malla","value":284.84,"unit":"m","source":"Malla de proyecto y origen altimétrico 285 m","status":"derivado"},{"label":"Cota máxima absoluta de la malla","value":290.85,"unit":"m","source":"Malla de proyecto y origen altimétrico 285 m","status":"derivado"},{"label":"Volumen geométrico bruto","value":0.085835,"unit":"m³","source":"Malla cerrada del elemento","status":"derivado"}],"notes":["Las dimensiones documentadas proceden de anotaciones o cuadros; la caja y el volumen se calculan a partir de la malla.","El volumen es exclusivamente geométrico y bruto; no representa una medición neta de material ni una cantidad de compra."]} | {"documentId":"EST-SB-20260710","title":"Planos de estructura de la sala de bombas contra incendios","date":"2026-07-10","sheet":"Estructura A101 / p. 2, A402 / p. 9"} | ["Cabeza de pilar: +5,00 m en el eje A y +4,60 m en el eje B.","Uniones de pie de pilar no modeladas; arranque deducido de la cota de zapata o del detalle de placa de base disponible.","Registro de líneas del PDF general con envolvente de 10,2 × 8,2 m. Estimación de trabajo de implantación de ±0,15 m, pendiente de CAD nativo; no constituye una precisión topográfica garantizada."] | {"horizontalStatus":"derivado","verticalStatus":"provisional","baseElevationM":286.25,"note":"Registro de líneas del PDF general con envolvente de 10,2 × 8,2 m. Estimación de trabajo de implantación de ±0,15 m, pendiente de CAD nativo; no constituye una precisión topográfica garantizada."} | {"boundingBoxM":{"min":[18.774466,33.060052,-0.16],"max":[19.112531,33.398117,5.85]},"extentsM":[0.338065,0.338065,6.01],"meshSurfaceM2":10.714347,"meshVolumeM3":0.085834,"closedSolid":true,"basis":"Geometría triangulada releída del IFC; envolventes y magnitudes no contractuales."} | {"material":true,"document":true,"quantities":true,"containerGuid":"0Wh59pm9LO_einrwiq6Es1","containerName":"Planta baja"} | {"profileId":"steel_structural","name":"Acero estructural · protección gris","materialName":"Acero estructural S355JR","physicalMaterialStatus":"known","physicalMaterialSource":"EST-SB-20260710 · Estructura A101 / p. 2, A402 / p. 9","appearanceStatus":"criterio_visual","appearanceBasis":"S355JR consta en la documentación; protección superficial gris adoptada para visualización, sin especificación de pintura confirmada.","note":"La apariencia gráfica no modifica ni confirma la especificación física del material."} | {"elementId":"pump_house_0051","ifcGuid":"18iFzS3P1QmunScpZWaP1I","ifcClass":"IfcColumn","buildingId":"pump_house","buildingName":"Sala de bombas contra incendios","sourceDocumentId":"EST-SB-20260710","sourceRepresentationKind":"documentary_mesh"} | EST-SB-20260710 · Estructura A101 / p. 2, A402 / p. 9 | HEB300 | {"h":300.0,"b":300.0,"tw":11.0,"tf":19.0} | Cabeza de pilar: +5,00 m en el eje A y +4,60 m en el eje B. | Registro de líneas del PDF general con envolvente de 10,2 × 8,2 m. Estimación de trabajo de implantación de ±0,15 m, pendiente de CAD nativo; no constituye una precisión topográfica garantizada. | 286.25 | 300
Edificio de oficinas · pilar HEA400 · 1 | Planos de estructura del edificio de oficinas; Planos de estructura del edificio de oficinas | 0.3 × 0.39 × 6 | 284.95 | 290.95 | 0.091632 | office_0239 | 0.427227 | 0.350324 | 6 | 11.7785 | 0.0916329 | office | Edificio de oficinas | {"name":"Acero estructural S355JR","source":"EST-OF-20260710 · Estructura B102 / p. 3, B201 / p. 5","status":"known"} | {"documented":[{"label":"Perfil","value":"HEA400","unit":"designación","source":"EST-OF-20260710 · Estructura B102 / p. 3, B201 / p. 5","status":"documentado"},{"label":"Canto nominal del perfil","value":390,"unit":"mm","source":"Catálogo de perfiles ArcelorMittal · 84","status":"documentado"},{"label":"Anchura nominal de ala","value":300,"unit":"mm","source":"Catálogo de perfiles ArcelorMittal · 84","status":"documentado"},{"label":"Espesor nominal de alma","value":11,"unit":"mm","source":"Catálogo de perfiles ArcelorMittal · 84","status":"documentado"},{"label":"Espesor nominal de ala","value":19,"unit":"mm","source":"Catálogo de perfiles ArcelorMittal · 84","status":"documentado"}],"geometry":[{"label":"Dimensiones de la caja local del elemento (X, Y, Z)","value":"0.3 × 0.39 × 6","unit":"m","source":"Malla triangulada del elemento en ejes locales del edificio","status":"derivado"},{"label":"Cota mínima absoluta de la malla","value":284.95,"unit":"m","source":"Malla de proyecto y origen altimétrico 285 m","status":"derivado"},{"label":"Cota máxima absoluta de la malla","value":290.95,"unit":"m","source":"Malla de proyecto y origen altimétrico 285 m","status":"derivado"},{"label":"Volumen geométrico bruto","value":0.091632,"unit":"m³","source":"Malla cerrada del elemento","status":"derivado"}],"notes":["Las dimensiones documentadas proceden de anotaciones o cuadros; la caja y el volumen se calculan a partir de la malla.","El volumen es exclusivamente geométrico y bruto; no representa una medición neta de material ni una cantidad de compra."]} | {"documentId":"EST-OF-20260710","title":"Planos de estructura del edificio de oficinas","date":"2026-07-10","sheet":"Estructura B102 / p. 3, B201 / p. 5"} | ["Cabeza de pilar de oficinas a +5,00 m según B102; encuentro con la placa de cubierta a +4,45 m pendiente de revisión de diseño.","El plano general de 2026-07-31 mantiene el edificio de oficinas de 200 m², mientras documentación anterior indica su supresión. Se conserva lo dibujado, pendiente de confirmación de la propiedad y del equipo de diseño.","Uniones de pie de pilar no modeladas; arranque deducido de la cota de zapata o del detalle de placa de base disponible.","Registro de líneas del PDF general, envolvente de 20 × 10 m; eje local 1 al norte y acceso del lado A al oeste. Estimación de trabajo de implantación de ±0,15 m, pendiente de CAD; no constituye una precisión topográfica garantizada."] | {"horizontalStatus":"derivado","verticalStatus":"provisional","baseElevationM":285.95,"note":"Registro de líneas del PDF general, envolvente de 20 × 10 m; eje local 1 al norte y acceso del lado A al oeste. Estimación de trabajo de implantación de ±0,15 m, pendiente de CAD; no constituye una precisión topográfica garantizada."} | {"boundingBoxM":{"min":[17.672669,92.342127,-0.05],"max":[18.099896,92.692451,5.95]},"extentsM":[0.427227,0.350324,6.0],"meshSurfaceM2":11.778527,"meshVolumeM3":0.091633,"closedSolid":true,"basis":"Geometría triangulada releída del IFC; envolventes y magnitudes no contractuales."} | {"material":true,"document":true,"quantities":true,"containerGuid":"3ztlotcerHPueDgxP84R6z","containerName":"Planta baja"} | {"profileId":"steel_structural","name":"Acero estructural · protección gris","materialName":"Acero estructural S355JR","physicalMaterialStatus":"known","physicalMaterialSource":"EST-OF-20260710 · Estructura B102 / p. 3, B201 / p. 5","appearanceStatus":"criterio_visual","appearanceBasis":"S355JR consta en la documentación; protección superficial gris adoptada para visualización, sin especificación de pintura confirmada.","note":"La apariencia gráfica no modifica ni confirma la especificación física del material."} | {"elementId":"office_0239","ifcGuid":"1xv8GaDkLOIOLHhEWOcSZM","ifcClass":"IfcColumn","buildingId":"office","buildingName":"Edificio de oficinas","sourceDocumentId":"EST-OF-20260710","sourceRepresentationKind":"documentary_mesh"} | EST-OF-20260710 · Estructura B102 / p. 3, B201 / p. 5 | HEA400 | {"h":390.0,"b":300.0,"tw":11.0,"tf":19.0} | Cabeza de pilar de oficinas a +5,00 m según B102; encuentro con la placa de cubierta a +4,45 m pendiente de revisión de diseño. | Registro de líneas del PDF general, envolvente de 20 × 10 m; eje local 1 al norte y acceso del lado A al oeste. Estimación de trabajo de implantación de ±0,15 m, pendiente de CAD; no constituye una precisión topográfica garantizada. | 285.95 | 390 | El plano general de 2026-07-31 mantiene el edificio de oficinas de 200 m², mientras documentación anterior indica su supresión. Se conserva lo dibujado, pendiente de confirmación de la propiedad y del equipo de diseño.
Edificio de oficinas · pilar HEA400 · 2 | Planos de estructura del edificio de oficinas; Planos de estructura del edificio de oficinas | 0.3 × 0.39 × 6 | 284.95 | 290.95 | 0.091632 | office_0240 | 0.427227 | 0.350324 | 6 | 11.7785 | 0.0916328 | office | Edificio de oficinas | {"name":"Acero estructural S355JR","source":"EST-OF-20260710 · Estructura B102 / p. 3, B201 / p. 5","status":"known"} | {"documented":[{"label":"Perfil","value":"HEA400","unit":"designación","source":"EST-OF-20260710 · Estructura B102 / p. 3, B201 / p. 5","status":"documentado"},{"label":"Canto nominal del perfil","value":390,"unit":"mm","source":"Catálogo de perfiles ArcelorMittal · 84","status":"documentado"},{"label":"Anchura nominal de ala","value":300,"unit":"mm","source":"Catálogo de perfiles ArcelorMittal · 84","status":"documentado"},{"label":"Espesor nominal de alma","value":11,"unit":"mm","source":"Catálogo de perfiles ArcelorMittal · 84","status":"documentado"},{"label":"Espesor nominal de ala","value":19,"unit":"mm","source":"Catálogo de perfiles ArcelorMittal · 84","status":"documentado"}],"geometry":[{"label":"Dimensiones de la caja local del elemento (X, Y, Z)","value":"0.3 × 0.39 × 6","unit":"m","source":"Malla triangulada del elemento en ejes locales del edificio","status":"derivado"},{"label":"Cota mínima absoluta de la malla","value":284.95,"unit":"m","source":"Malla de proyecto y origen altimétrico 285 m","status":"derivado"},{"label":"Cota máxima absoluta de la malla","value":290.95,"unit":"m","source":"Malla de proyecto y origen altimétrico 285 m","status":"derivado"},{"label":"Volumen geométrico bruto","value":0.091632,"unit":"m³","source":"Malla cerrada del elemento","status":"derivado"}],"notes":["Las dimensiones documentadas proceden de anotaciones o cuadros; la caja y el volumen se calculan a partir de la malla.","El volumen es exclusivamente geométrico y bruto; no representa una medición neta de material ni una cantidad de compra."]} | {"documentId":"EST-OF-20260710","title":"Planos de estructura del edificio de oficinas","date":"2026-07-10","sheet":"Estructura B102 / p. 3, B201 / p. 5"} | ["Cabeza de pilar de oficinas a +5,00 m según B102; encuentro con la placa de cubierta a +4,45 m pendiente de revisión de diseño.","El plano general de 2026-07-31 mantiene el edificio de oficinas de 200 m², mientras documentación anterior indica su supresión. Se conserva lo dibujado, pendiente de confirmación de la propiedad y del equipo de diseño.","Uniones de pie de pilar no modeladas; arranque deducido de la cota de zapata o del detalle de placa de base disponible.","Registro de líneas del PDF general, envolvente de 20 × 10 m; eje local 1 al norte y acceso del lado A al oeste. Estimación de trabajo de implantación de ±0,15 m, pendiente de CAD; no constituye una precisión topográfica garantizada."] | {"horizontalStatus":"derivado","verticalStatus":"provisional","baseElevationM":285.95,"note":"Registro de líneas del PDF general, envolvente de 20 × 10 m; eje local 1 al norte y acceso del lado A al oeste. Estimación de trabajo de implantación de ±0,15 m, pendiente de CAD; no constituye una precisión topográfica garantizada."} | {"boundingBoxM":{"min":[16.358301,82.782057,-0.05],"max":[16.785528,83.132381,5.95]},"extentsM":[0.427227,0.350324,6.0],"meshSurfaceM2":11.77854,"meshVolumeM3":0.091633,"closedSolid":true,"basis":"Geometría triangulada releída del IFC; envolventes y magnitudes no contractuales."} | {"material":true,"document":true,"quantities":true,"containerGuid":"3ztlotcerHPueDgxP84R6z","containerName":"Planta baja"} | {"profileId":"steel_structural","name":"Acero estructural · protección gris","materialName":"Acero estructural S355JR","physicalMaterialStatus":"known","physicalMaterialSource":"EST-OF-20260710 · Estructura B102 / p. 3, B201 / p. 5","appearanceStatus":"criterio_visual","appearanceBasis":"S355JR consta en la documentación; protección superficial gris adoptada para visualización, sin especificación de pintura confirmada.","note":"La apariencia gráfica no modifica ni confirma la especificación física del material."} | {"elementId":"office_0240","ifcGuid":"2xwI8BW49O2P4Npnmn_jTD","ifcClass":"IfcColumn","buildingId":"office","buildingName":"Edificio de oficinas","sourceDocumentId":"EST-OF-20260710","sourceRepresentationKind":"documentary_mesh"} | EST-OF-20260710 · Estructura B102 / p. 3, B201 / p. 5 | HEA400 | {"h":390.0,"b":300.0,"tw":11.0,"tf":19.0} | Cabeza de pilar de oficinas a +5,00 m según B102; encuentro con la placa de cubierta a +4,45 m pendiente de revisión de diseño. | Registro de líneas del PDF general, envolvente de 20 × 10 m; eje local 1 al norte y acceso del lado A al oeste. Estimación de trabajo de implantación de ±0,15 m, pendiente de CAD; no constituye una precisión topográfica garantizada. | 285.95 | 390 | El plano general de 2026-07-31 mantiene el edificio de oficinas de 200 m², mientras documentación anterior indica su supresión. Se conserva lo dibujado, pendiente de confirmación de la propiedad y del equipo de diseño.
Edificio de oficinas · pilar HEA400 · 3 | Planos de estructura del edificio de oficinas; Planos de estructura del edificio de oficinas | 0.3 × 0.39 × 6 | 284.95 | 290.95 | 0.091632 | office_0241 | 0.427226 | 0.350324 | 6 | 11.7785 | 0.0916313 | office | Edificio de oficinas | {"name":"Acero estructural S355JR","source":"EST-OF-20260710 · Estructura B102 / p. 3, B201 / p. 5","status":"known"} | {"documented":[{"label":"Perfil","value":"HEA400","unit":"designación","source":"EST-OF-20260710 · Estructura B102 / p. 3, B201 / p. 5","status":"documentado"},{"label":"Canto nominal del perfil","value":390,"unit":"mm","source":"Catálogo de perfiles ArcelorMittal · 84","status":"documentado"},{"label":"Anchura nominal de ala","value":300,"unit":"mm","source":"Catálogo de perfiles ArcelorMittal · 84","status":"documentado"},{"label":"Espesor nominal de alma","value":11,"unit":"mm","source":"Catálogo de perfiles ArcelorMittal · 84","status":"documentado"},{"label":"Espesor nominal de ala","value":19,"unit":"mm","source":"Catálogo de perfiles ArcelorMittal · 84","status":"documentado"}],"geometry":[{"label":"Dimensiones de la caja local del elemento (X, Y, Z)","value":"0.3 × 0.39 × 6","unit":"m","source":"Malla triangulada del elemento en ejes locales del edificio","status":"derivado"},{"label":"Cota mínima absoluta de la malla","value":284.95,"unit":"m","source":"Malla de proyecto y origen altimétrico 285 m","status":"derivado"},{"label":"Cota máxima absoluta de la malla","value":290.95,"unit":"m","source":"Malla de proyecto y origen altimétrico 285 m","status":"derivado"},{"label":"Volumen geométrico bruto","value":0.091632,"unit":"m³","source":"Malla cerrada del elemento","status":"derivado"}],"notes":["Las dimensiones documentadas proceden de anotaciones o cuadros; la caja y el volumen se calculan a partir de la malla.","El volumen es exclusivamente geométrico y bruto; no representa una medición neta de material ni una cantidad de compra."]} | {"documentId":"EST-OF-20260710","title":"Planos de estructura del edificio de oficinas","date":"2026-07-10","sheet":"Estructura B102 / p. 3, B201 / p. 5"} | ["Cabeza de pilar de oficinas a +5,00 m según B102; encuentro con la placa de cubierta a +4,45 m pendiente de revisión de diseño.","El plano general de 2026-07-31 mantiene el edificio de oficinas de 200 m², mientras documentación anterior indica su supresión. Se conserva lo dibujado, pendiente de confirmación de la propiedad y del equipo de diseño.","Uniones de pie de pilar no modeladas; arranque deducido de la cota de zapata o del detalle de placa de base disponible.","Registro de líneas del PDF general, envolvente de 20 × 10 m; eje local 1 al norte y acceso del lado A al oeste. Estimación de trabajo de implantación de ±0,15 m, pendiente de CAD; no constituye una precisión topográfica garantizada."] | {"horizontalStatus":"derivado","verticalStatus":"provisional","baseElevationM":285.95,"note":"Registro de líneas del PDF general, envolvente de 20 × 10 m; eje local 1 al norte y acceso del lado A al oeste. Estimación de trabajo de implantación de ±0,15 m, pendiente de CAD; no constituye una precisión topográfica garantizada."} | {"boundingBoxM":{"min":[15.043934,73.221987,-0.05],"max":[15.47116,73.572311,5.95]},"extentsM":[0.427226,0.350324,6.0],"meshSurfaceM2":11.778548,"meshVolumeM3":0.091631,"closedSolid":true,"basis":"Geometría triangulada releída del IFC; envolventes y magnitudes no contractuales."} | {"material":true,"document":true,"quantities":true,"containerGuid":"3ztlotcerHPueDgxP84R6z","containerName":"Planta baja"} | {"profileId":"steel_structural","name":"Acero estructural · protección gris","materialName":"Acero estructural S355JR","physicalMaterialStatus":"known","physicalMaterialSource":"EST-OF-20260710 · Estructura B102 / p. 3, B201 / p. 5","appearanceStatus":"criterio_visual","appearanceBasis":"S355JR consta en la documentación; protección superficial gris adoptada para visualización, sin especificación de pintura confirmada.","note":"La apariencia gráfica no modifica ni confirma la especificación física del material."} | {"elementId":"office_0241","ifcGuid":"0sk4XszWbMWPyqkLCnVyDc","ifcClass":"IfcColumn","buildingId":"office","buildingName":"Edificio de oficinas","sourceDocumentId":"EST-OF-20260710","sourceRepresentationKind":"documentary_mesh"} | EST-OF-20260710 · Estructura B102 / p. 3, B201 / p. 5 | HEA400 | {"h":390.0,"b":300.0,"tw":11.0,"tf":19.0} | Cabeza de pilar de oficinas a +5,00 m según B102; encuentro con la placa de cubierta a +4,45 m pendiente de revisión de diseño. | Registro de líneas del PDF general, envolvente de 20 × 10 m; eje local 1 al norte y acceso del lado A al oeste. Estimación de trabajo de implantación de ±0,15 m, pendiente de CAD; no constituye una precisión topográfica garantizada. | 285.95 | 390 | El plano general de 2026-07-31 mantiene el edificio de oficinas de 200 m², mientras documentación anterior indica su supresión. Se conserva lo dibujado, pendiente de confirmación de la propiedad y del equipo de diseño.
Edificio de oficinas · pilar HEA400 · 4 | Planos de estructura del edificio de oficinas; Planos de estructura del edificio de oficinas | 0.3 × 0.39 × 6 | 284.95 | 290.95 | 0.091632 | office_0242 | 0.427226 | 0.350324 | 6 | 11.7785 | 0.0916313 | office | Edificio de oficinas | {"name":"Acero estructural S355JR","source":"EST-OF-20260710 · Estructura B102 / p. 3, B201 / p. 5","status":"known"} | {"documented":[{"label":"Perfil","value":"HEA400","unit":"designación","source":"EST-OF-20260710 · Estructura B102 / p. 3, B201 / p. 5","status":"documentado"},{"label":"Canto nominal del perfil","value":390,"unit":"mm","source":"Catálogo de perfiles ArcelorMittal · 84","status":"documentado"},{"label":"Anchura nominal de ala","value":300,"unit":"mm","source":"Catálogo de perfiles ArcelorMittal · 84","status":"documentado"},{"label":"Espesor nominal de alma","value":11,"unit":"mm","source":"Catálogo de perfiles ArcelorMittal · 84","status":"documentado"},{"label":"Espesor nominal de ala","value":19,"unit":"mm","source":"Catálogo de perfiles ArcelorMittal · 84","status":"documentado"}],"geometry":[{"label":"Dimensiones de la caja local del elemento (X, Y, Z)","value":"0.3 × 0.39 × 6","unit":"m","source":"Malla triangulada del elemento en ejes locales del edificio","status":"derivado"},{"label":"Cota mínima absoluta de la malla","value":284.95,"unit":"m","source":"Malla de proyecto y origen altimétrico 285 m","status":"derivado"},{"label":"Cota máxima absoluta de la malla","value":290.95,"unit":"m","source":"Malla de proyecto y origen altimétrico 285 m","status":"derivado"},{"label":"Volumen geométrico bruto","value":0.091632,"unit":"m³","source":"Malla cerrada del elemento","status":"derivado"}],"notes":["Las dimensiones documentadas proceden de anotaciones o cuadros; la caja y el volumen se calculan a partir de la malla.","El volumen es exclusivamente geométrico y bruto; no representa una medición neta de material ni una cantidad de compra."]} | {"documentId":"EST-OF-20260710","title":"Planos de estructura del edificio de oficinas","date":"2026-07-10","sheet":"Estructura B102 / p. 3, B201 / p. 5"} | ["Cabeza de pilar de oficinas a +5,00 m según B102; encuentro con la placa de cubierta a +4,45 m pendiente de revisión de diseño.","El plano general de 2026-07-31 mantiene el edificio de oficinas de 200 m², mientras documentación anterior indica su supresión. Se conserva lo dibujado, pendiente de confirmación de la propiedad y del equipo de diseño.","Uniones de pie de pilar no modeladas; arranque deducido de la cota de zapata o del detalle de placa de base disponible.","Registro de líneas del PDF general, envolvente de 20 × 10 m; eje local 1 al norte y acceso del lado A al oeste. Estimación de trabajo de implantación de ±0,15 m, pendiente de CAD; no constituye una precisión topográfica garantizada."] | {"horizontalStatus":"derivado","verticalStatus":"provisional","baseElevationM":285.95,"note":"Registro de líneas del PDF general, envolvente de 20 × 10 m; eje local 1 al norte y acceso del lado A al oeste. Estimación de trabajo de implantación de ±0,15 m, pendiente de CAD; no constituye una precisión topográfica garantizada."} | {"boundingBoxM":{"min":[26.79684,91.087689,-0.05],"max":[27.224066,91.438013,5.95]},"extentsM":[0.427226,0.350324,6.0],"meshSurfaceM2":11.778548,"meshVolumeM3":0.091631,"closedSolid":true,"basis":"Geometría triangulada releída del IFC; envolventes y magnitudes no contractuales."} | {"material":true,"document":true,"quantities":true,"containerGuid":"3ztlotcerHPueDgxP84R6z","containerName":"Planta baja"} | {"profileId":"steel_structural","name":"Acero estructural · protección gris","materialName":"Acero estructural S355JR","physicalMaterialStatus":"known","physicalMaterialSource":"EST-OF-20260710 · Estructura B102 / p. 3, B201 / p. 5","appearanceStatus":"criterio_visual","appearanceBasis":"S355JR consta en la documentación; protección superficial gris adoptada para visualización, sin especificación de pintura confirmada.","note":"La apariencia gráfica no modifica ni confirma la especificación física del material."} | {"elementId":"office_0242","ifcGuid":"3JFBcUWYfJtPCG5T826_i3","ifcClass":"IfcColumn","buildingId":"office","buildingName":"Edificio de oficinas","sourceDocumentId":"EST-OF-20260710","sourceRepresentationKind":"documentary_mesh"} | EST-OF-20260710 · Estructura B102 / p. 3, B201 / p. 5 | HEA400 | {"h":390.0,"b":300.0,"tw":11.0,"tf":19.0} | Cabeza de pilar de oficinas a +5,00 m según B102; encuentro con la placa de cubierta a +4,45 m pendiente de revisión de diseño. | Registro de líneas del PDF general, envolvente de 20 × 10 m; eje local 1 al norte y acceso del lado A al oeste. Estimación de trabajo de implantación de ±0,15 m, pendiente de CAD; no constituye una precisión topográfica garantizada. | 285.95 | 390 | El plano general de 2026-07-31 mantiene el edificio de oficinas de 200 m², mientras documentación anterior indica su supresión. Se conserva lo dibujado, pendiente de confirmación de la propiedad y del equipo de diseño.
Edificio de oficinas · pilar HEA400 · 5 | Planos de estructura del edificio de oficinas; Planos de estructura del edificio de oficinas | 0.3 × 0.39 × 6 | 284.95 | 290.95 | 0.091632 | office_0243 | 0.427227 | 0.350324 | 6 | 11.7785 | 0.0916328 | office | Edificio de oficinas | {"name":"Acero estructural S355JR","source":"EST-OF-20260710 · Estructura B102 / p. 3, B201 / p. 5","status":"known"} | {"documented":[{"label":"Perfil","value":"HEA400","unit":"designación","source":"EST-OF-20260710 · Estructura B102 / p. 3, B201 / p. 5","status":"documentado"},{"label":"Canto nominal del perfil","value":390,"unit":"mm","source":"Catálogo de perfiles ArcelorMittal · 84","status":"documentado"},{"label":"Anchura nominal de ala","value":300,"unit":"mm","source":"Catálogo de perfiles ArcelorMittal · 84","status":"documentado"},{"label":"Espesor nominal de alma","value":11,"unit":"mm","source":"Catálogo de perfiles ArcelorMittal · 84","status":"documentado"},{"label":"Espesor nominal de ala","value":19,"unit":"mm","source":"Catálogo de perfiles ArcelorMittal · 84","status":"documentado"}],"geometry":[{"label":"Dimensiones de la caja local del elemento (X, Y, Z)","value":"0.3 × 0.39 × 6","unit":"m","source":"Malla triangulada del elemento en ejes locales del edificio","status":"derivado"},{"label":"Cota mínima absoluta de la malla","value":284.95,"unit":"m","source":"Malla de proyecto y origen altimétrico 285 m","status":"derivado"},{"label":"Cota máxima absoluta de la malla","value":290.95,"unit":"m","source":"Malla de proyecto y origen altimétrico 285 m","status":"derivado"},{"label":"Volumen geométrico bruto","value":0.091632,"unit":"m³","source":"Malla cerrada del elemento","status":"derivado"}],"notes":["Las dimensiones documentadas proceden de anotaciones o cuadros; la caja y el volumen se calculan a partir de la malla.","El volumen es exclusivamente geométrico y bruto; no representa una medición neta de material ni una cantidad de compra."]} | {"documentId":"EST-OF-20260710","title":"Planos de estructura del edificio de oficinas","date":"2026-07-10","sheet":"Estructura B102 / p. 3, B201 / p. 5"} | ["Cabeza de pilar de oficinas a +5,00 m según B102; encuentro con la placa de cubierta a +4,45 m pendiente de revisión de diseño.","El plano general de 2026-07-31 mantiene el edificio de oficinas de 200 m², mientras documentación anterior indica su supresión. Se conserva lo dibujado, pendiente de confirmación de la propiedad y del equipo de diseño.","Uniones de pie de pilar no modeladas; arranque deducido de la cota de zapata o del detalle de placa de base disponible.","Registro de líneas del PDF general, envolvente de 20 × 10 m; eje local 1 al norte y acceso del lado A al oeste. Estimación de trabajo de implantación de ±0,15 m, pendiente de CAD; no constituye una precisión topográfica garantizada."] | {"horizontalStatus":"derivado","verticalStatus":"provisional","baseElevationM":285.95,"note":"Registro de líneas del PDF general, envolvente de 20 × 10 m; eje local 1 al norte y acceso del lado A al oeste. Estimación de trabajo de implantación de ±0,15 m, pendiente de CAD; no constituye una precisión topográfica garantizada."} | {"boundingBoxM":{"min":[25.482472,81.527619,-0.05],"max":[25.909699,81.877943,5.95]},"extentsM":[0.427227,0.350324,6.0],"meshSurfaceM2":11.77854,"meshVolumeM3":0.091633,"closedSolid":true,"basis":"Geometría triangulada releída del IFC; envolventes y magnitudes no contractuales."} | {"material":true,"document":true,"quantities":true,"containerGuid":"3ztlotcerHPueDgxP84R6z","containerName":"Planta baja"} | {"profileId":"steel_structural","name":"Acero estructural · protección gris","materialName":"Acero estructural S355JR","physicalMaterialStatus":"known","physicalMaterialSource":"EST-OF-20260710 · Estructura B102 / p. 3, B201 / p. 5","appearanceStatus":"criterio_visual","appearanceBasis":"S355JR consta en la documentación; protección superficial gris adoptada para visualización, sin especificación de pintura confirmada.","note":"La apariencia gráfica no modifica ni confirma la especificación física del material."} | {"elementId":"office_0243","ifcGuid":"1Z4qtkxsPJuBHDoh4c4SN8","ifcClass":"IfcColumn","buildingId":"office","buildingName":"Edificio de oficinas","sourceDocumentId":"EST-OF-20260710","sourceRepresentationKind":"documentary_mesh"} | EST-OF-20260710 · Estructura B102 / p. 3, B201 / p. 5 | HEA400 | {"h":390.0,"b":300.0,"tw":11.0,"tf":19.0} | Cabeza de pilar de oficinas a +5,00 m según B102; encuentro con la placa de cubierta a +4,45 m pendiente de revisión de diseño. | Registro de líneas del PDF general, envolvente de 20 × 10 m; eje local 1 al norte y acceso del lado A al oeste. Estimación de trabajo de implantación de ±0,15 m, pendiente de CAD; no constituye una precisión topográfica garantizada. | 285.95 | 390 | El plano general de 2026-07-31 mantiene el edificio de oficinas de 200 m², mientras documentación anterior indica su supresión. Se conserva lo dibujado, pendiente de confirmación de la propiedad y del equipo de diseño.
Edificio de oficinas · pilar HEA400 · 6 | Planos de estructura del edificio de oficinas; Planos de estructura del edificio de oficinas | 0.3 × 0.39 × 6 | 284.95 | 290.95 | 0.091632 | office_0244 | 0.427227 | 0.350324 | 6 | 11.7785 | 0.0916329 | office | Edificio de oficinas | {"name":"Acero estructural S355JR","source":"EST-OF-20260710 · Estructura B102 / p. 3, B201 / p. 5","status":"known"} | {"documented":[{"label":"Perfil","value":"HEA400","unit":"designación","source":"EST-OF-20260710 · Estructura B102 / p. 3, B201 / p. 5","status":"documentado"},{"label":"Canto nominal del perfil","value":390,"unit":"mm","source":"Catálogo de perfiles ArcelorMittal · 84","status":"documentado"},{"label":"Anchura nominal de ala","value":300,"unit":"mm","source":"Catálogo de perfiles ArcelorMittal · 84","status":"documentado"},{"label":"Espesor nominal de alma","value":11,"unit":"mm","source":"Catálogo de perfiles ArcelorMittal · 84","status":"documentado"},{"label":"Espesor nominal de ala","value":19,"unit":"mm","source":"Catálogo de perfiles ArcelorMittal · 84","status":"documentado"}],"geometry":[{"label":"Dimensiones de la caja local del elemento (X, Y, Z)","value":"0.3 × 0.39 × 6","unit":"m","source":"Malla triangulada del elemento en ejes locales del edificio","status":"derivado"},{"label":"Cota mínima absoluta de la malla","value":284.95,"unit":"m","source":"Malla de proyecto y origen altimétrico 285 m","status":"derivado"},{"label":"Cota máxima absoluta de la malla","value":290.95,"unit":"m","source":"Malla de proyecto y origen altimétrico 285 m","status":"derivado"},{"label":"Volumen geométrico bruto","value":0.091632,"unit":"m³","source":"Malla cerrada del elemento","status":"derivado"}],"notes":["Las dimensiones documentadas proceden de anotaciones o cuadros; la caja y el volumen se calculan a partir de la malla.","El volumen es exclusivamente geométrico y bruto; no representa una medición neta de material ni una cantidad de compra."]} | {"documentId":"EST-OF-20260710","title":"Planos de estructura del edificio de oficinas","date":"2026-07-10","sheet":"Estructura B102 / p. 3, B201 / p. 5"} | ["Cabeza de pilar de oficinas a +5,00 m según B102; encuentro con la placa de cubierta a +4,45 m pendiente de revisión de diseño.","El plano general de 2026-07-31 mantiene el edificio de oficinas de 200 m², mientras documentación anterior indica su supresión. Se conserva lo dibujado, pendiente de confirmación de la propiedad y del equipo de diseño.","Uniones de pie de pilar no modeladas; arranque deducido de la cota de zapata o del detalle de placa de base disponible.","Registro de líneas del PDF general, envolvente de 20 × 10 m; eje local 1 al norte y acceso del lado A al oeste. Estimación de trabajo de implantación de ±0,15 m, pendiente de CAD; no constituye una precisión topográfica garantizada."] | {"horizontalStatus":"derivado","verticalStatus":"provisional","baseElevationM":285.95,"note":"Registro de líneas del PDF general, envolvente de 20 × 10 m; eje local 1 al norte y acceso del lado A al oeste. Estimación de trabajo de implantación de ±0,15 m, pendiente de CAD; no constituye una precisión topográfica garantizada."} | {"boundingBoxM":{"min":[24.168104,71.967549,-0.05],"max":[24.595331,72.317873,5.95]},"extentsM":[0.427227,0.350324,6.0],"meshSurfaceM2":11.778527,"meshVolumeM3":0.091633,"closedSolid":true,"basis":"Geometría triangulada releída del IFC; envolventes y magnitudes no contractuales."} | {"material":true,"document":true,"quantities":true,"containerGuid":"3ztlotcerHPueDgxP84R6z","containerName":"Planta baja"} | {"profileId":"steel_structural","name":"Acero estructural · protección gris","materialName":"Acero estructural S355JR","physicalMaterialStatus":"known","physicalMaterialSource":"EST-OF-20260710 · Estructura B102 / p. 3, B201 / p. 5","appearanceStatus":"criterio_visual","appearanceBasis":"S355JR consta en la documentación; protección superficial gris adoptada para visualización, sin especificación de pintura confirmada.","note":"La apariencia gráfica no modifica ni confirma la especificación física del material."} | {"elementId":"office_0244","ifcGuid":"2yLXZlpJvJQPmsJpnpx9b5","ifcClass":"IfcColumn","buildingId":"office","buildingName":"Edificio de oficinas","sourceDocumentId":"EST-OF-20260710","sourceRepresentationKind":"documentary_mesh"} | EST-OF-20260710 · Estructura B102 / p. 3, B201 / p. 5 | HEA400 | {"h":390.0,"b":300.0,"tw":11.0,"tf":19.0} | Cabeza de pilar de oficinas a +5,00 m según B102; encuentro con la placa de cubierta a +4,45 m pendiente de revisión de diseño. | Registro de líneas del PDF general, envolvente de 20 × 10 m; eje local 1 al norte y acceso del lado A al oeste. Estimación de trabajo de implantación de ±0,15 m, pendiente de CAD; no constituye una precisión topográfica garantizada. | 285.95 | 390 | El plano general de 2026-07-31 mantiene el edificio de oficinas de 200 m², mientras documentación anterior indica su supresión. Se conserva lo dibujado, pendiente de confirmación de la propiedad y del equipo de diseño.

# IfcCompressor: Envolvente de equipo (3)
In: Parcela industrial Jinhong
Description: Componente de equipo · envolvente exterior; PredefinedType: USERDEFINED; Document: Plano del fabricante: cargas de equipos; Plano del fabricante: implantación de equipos · referencia E7; Cimentaciones de equipos y pedestales del fabricante · revisión recibida 04/09/2026; Group: Equipos; Zona de separación de aire; BIM · Envolventes de equipos
JH_CoordinacionCimentaciones - Relacion: Correspondencia documental; no verifica anclajes ni cotas de montaje.
JH_DimensionesDelModelo - Extensión de la malla en Y: 2.19286 m; Extensión de la malla en Z: 2.3 m; Cota inferior de visualización: 286.65 m; Cota superior de visualización: 288.95 m
JH_MagnitudesGeometricas - ExtensionY: 2.19286 m; ExtensionZ: 2.3 m; SuperficieDeLaMalla: 15.9397 m2; VolumenGeometrico: 3.31696 m3
JH_InformacionBIM - buildingId: process_plant; buildingName: Planta de proceso; level: Apoyo relativo +0.400 m; cero absoluto provisional; category: Componente de equipo · envolvente exterior; ifcClass: IfcCompressor; material: {"name":"No especificado","source":"Sin especificación de material en la documentación revisada","status":"unknown"}; source: {"documentId":"EQ-IMPLANTACION-20260430","title":"Plano del fabricante: implantación de equipos","sheet":"LHD2609-GD01000 · espacio modelo","date":"2026-04-30","componentSourceHandles":["732E7","73405","73406","73407","7340A","73441"]}; status: provisional; issues: ["Componente separado de una reconstrucción documental del conjunto. Las alturas y detalles parciales conservan las limitaciones del fabricante registradas en parentEquipmentIssues.","Esta representación exterior no crea una chapa hueca ni añade componentes internos no documentados.","La pertenencia al conjunto no demuestra apoyo o anclaje directo a la cimentación."]; ifcAssociations: {"material":false,"document":true,"quantities":true,"containerGuid":"17utmjd_LKsAVvPyuSUhFt","containerName":"Parcela industrial Jinhong"}; installationSource: {"documentId":"LHD2609-JG00100-20260904","title":"Cimentaciones y pedestales de equipos · revisión recibida 04/09/2026","date":"2026-09-04","sheet":"1 / 1-1","sourceHandles":["28C35","28C38","28C3B","28C89"]}; representationKind: equipmentComponent; parentEquipmentIfcClass: IfcCompressor; parentEquipmentPositioning: {"Estado de la planta":"Derivado del CAD y del giro de implantación","Nivel relativo del apoyo (m)":0.4,"Estado del nivel relativo":"Documentado en el plano de cimentaciones","Cero absoluto de visualización (m)":286.1,"Estado del cero absoluto":"Provisional","Cota del apoyo de visualización (m)":286.5,"Desplazamiento aplicado a la malla (m)":0.40000000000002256,"Criterio":"Nivel de apoyo relativo documentado. Se adopta el cero de proceso a 286,10 m solo para visualización; la equivalencia absoluta no está confirmada. No se añade un espesor de montaje sin cota del fabricante."}; parentEquipmentIssues: ["La máquina está contenida en la envolvente de la cabina acústica; su superposición no acredita una interferencia física.","El bastidor CAD coincide con la referencia de 2,35 × 5,22 m del plano de cargas, pero cuerpos y auxiliares del detalle de abril sobresalen de esa referencia, hasta aproximadamente 1,048 m por el extremo sur y 0,246 m por el lado oeste. Extensión geométrica resultante: 2,595899 × 6,268101 × 3,38 m, derivada y pendiente de coordinación entre revisiones. Permanecen dentro de la cabina acústica. Compatibilidad de revisión pendiente de fabricante.","Todas las alturas parciales son hipótesis de visualización; solo la altura total de 3,38 m está acotada.","Las regiones del dibujo se usan como envolventes de cuerpos; la identificación funcional y la cota Z de cada pieza requieren verificación.","Pequeños taladros, tornillería y detalles interiores de las regiones no se extruyen como vacíos de fabricación.","El bastidor documentado mide 2,35 × 5,22 m. Los accesorios del detalle de abril sobresalen; el conjunto refinado ocupa aproximadamente 2,596 × 6,268 m en ejes del fabricante, pendiente de coordinación entre revisiones.","El acabado de grout HA-35 de 50 mm termina en +0,400; el hormigón termina en +0,350. La losa MAC contigua termina en +0,200.","El cero absoluto de la revisión no está definido; 286,10 m sigue siendo una hipótesis de coordinación.","Se alinea el punto inferior del conjunto del equipo, incluidos los pies ya representados, con la superficie de apoyo terminada; no se añade un espesor de calzos, placa o grout del fabricante no documentado."]; parentEquipmentDetail: {"revision":"Detalle en planta de 2026-04-30 coordinado de forma preliminar con envolventes y alturas de 2026-08-25","status":"provisional","verticalRule":"Altura total documentada: 3,38 m. Plataforma gráfica de 0,15 m; los cuerpos extraídos de la planta reciben alturas provisionales entre 1,00 y 3,38 m, detalladas por subvolumen. No se dispone de alzado acotado de cada componente.","partCount":26,"source":{"documentId":"EQ-IMPLANTACION-20260430","title":"Plano del fabricante: implantación de equipos","sheet":"LHD2609-GD01000 · espacio modelo","date":"2026-04-30"},"heightSource":{"documentId":"EQ-CARGAS-20260825","title":"Plano del fabricante: cargas de equipos","sheet":"Espacio modelo","date":"2026-08-25"},"unconfirmedDimensions":["Todas las alturas parciales son hipótesis de visualización; solo la altura total de 3,38 m está acotada.","Las regiones del dibujo se usan como envolventes de cuerpos; la identificación funcional y la cota Z de cada pieza requieren verificación.","Pequeños taladros, tornillería y detalles interiores de las regiones no se extruyen como vacíos de fabricación."],"quantityUse":"Magnitudes de la geometría representada; no son cantidades de material, obra, compra, capacidad útil ni fabricación. En geometrías compuestas se suman superficies y volúmenes de partes y pueden existir solapes no depurados.","partsAreBOM":false}; componentRole: provisional_casing_region; manufacturerDetailsPending: ["Todas las alturas parciales son hipótesis de visualización; solo la altura total de 3,38 m está acotada.","Las regiones del dibujo se usan como envolventes de cuerpos; la identificación funcional y la cota Z de cada pieza requieren verificación.","Pequeños taladros, tornillería y detalles interiores de las regiones no se extruyen como vacíos de fabricación.","La separación gráfica no aporta cotas de fabricación ni identifica piezas internas no documentadas.","Los materiales y acabados permanecen provisionales; las fotografías públicas solo orientan la apariencia."]; visualLayer: {"id":"equipment_enclosures","name":"Envolventes de equipos"}; materialAppearance: {"profileId":"equipment_light_gray","name":"Equipo · gris claro provisional","materialName":"No especificado","physicalMaterialStatus":"unknown","physicalMaterialSource":"Sin especificación de material en la documentación revisada","appearanceStatus":"provisional","appearanceBasis":"Referencia visual de fotografías públicas de Jinhong Gas / fabricante. Apariencia provisional para coordinación; fotografías oficiales pueden orientar el color, pero no acreditan el material, el acabado ni el equipo concreto.","appearanceReferences":["jinhong-official-asu"],"note":"El perfil visual no confirma material, grado ni acabado del componente."}; installationSourceScope: Documento de implantación y apoyo del conjunto padre; no acredita fijación individual de este componente.; mainComponentSelectionBasis: Mayor volumen geométrico entre las regiones CAD etiquetadas Carcasa principal; selección administrativa para conservar el GUID del equipo, no identificación de fabricante adicional.; classification: {"layerId":"equipment_enclosures","layerName":"Envolventes de equipos","role":"Componente de equipo · envolvente exterior","basis":"Clasificación por función del elemento; no modifica las especificaciones documentales."}; layerId: equipment_enclosures; appearance: {"profileId":"equipment_light_gray","name":"Equipo · gris claro provisional","status":"provisional","basis":"Referencia visual de fotografías públicas de Jinhong Gas / fabricante. Apariencia provisional para coordinación; fotografías oficiales pueden orientar el color, pero no acreditan el material, el acabado ni el equipo concreto.","physicalMaterialUnchanged":true}
JH_Trazabilidad - Referencia en el plano del fabricante: 1; Documento de origen: Plano del fabricante: cargas de equipos · 2026-08-25 · Espacio modelo; número de plano no identificado; Documento CAD derivado: Conversión DXF del plano de cargas de equipos · 2026-08-25 · espacio modelo; Capa CAD de referencia: Anotaciones y contornos de equipos; Cota de altura del fabricante (traducción): Altura del equipo: 3.38m; Altura (m): 3.38; Origen de las dimensiones: Plano de cargas del fabricante de 2026-08-25: lectura directa del contorno CAD cerrado y de la cota de altura del equipo.; Grado de definición: Planta derivada del CAD, altura total documentada y alturas parciales provisionales.; Alcance de la geometría: Geometría compuesta con perfiles CAD y distribución vertical provisional; véase Detalle geométrico.; Origen de la posición: Punto de referencia del fabricante: entidad CIRCLE, handle 98, en la esquina inferior izquierda de la zona de equipos. Los ejes X e Y son locales y se giran para su implantación UTM.; Hipótesis de modelado: Nivel de apoyo relativo documentado. Se adopta el cero de proceso a 286,10 m solo para visualización; la equivalencia absoluta no está confirmada. No se añade un espesor de montaje sin cota del fabricante.; Observaciones: Envolvente de la máquina interior contenida en la cabina acústica. Su superposición representa esa relación de contención; ambos grupos pueden visualizarse por separado.; Masa propia indicada (kg): 30000; Dimensiones de la plataforma de equipos (m): 27 × 57 m; dimensiones acotadas en el plano general.; Implantación de la plataforma de equipos: El punto de referencia del fabricante coincide con la esquina suroeste de la zona de equipos. Giro local de −7,82824° para la implantación en coordenadas UTM.; Estado de la cota de instalación: Nivel de apoyo relativo documentado. Se adopta el cero de proceso a 286,10 m solo para visualización; la equivalencia absoluta no está confirmada. No se añade un espesor de montaje sin cota del fabricante.; Convención de coordenadas: Coordenadas locales del proyecto en metros. Añadir (729400, 4301550, 285) para recuperar las coordenadas UTM y las cotas del plano.; Disciplina: Envolventes de equipos; Clase IFC: IfcCompressor; Fase del modelo: Revisión de la zona de separación de aire · septiembre de 2026; Representación geométrica IFC: Sólido IFC4 mediante malla triangular cerrada; Aplicabilidad a mediciones: Magnitudes de la geometría representada; no son cantidades de material, obra, compra, capacidad útil ni fabricación. En geometrías compuestas se suman superficies y volúmenes de partes y pueden existir solapes no depurados.; Material: No especificado; Estado de la información: provisional; Detalle geométrico: derivado; Incidencias del detalle: ["Nivel de apoyo relativo documentado. Se adopta el cero de proceso a 286,10 m solo para visualización; la equivalencia absoluta no está confirmada. No se añade un espesor de montaje sin cota del fabricante.","La máquina está contenida en la envolvente de la cabina acústica; su superposición no acredita una interferencia física.","El bastidor CAD coincide con la referencia de 2,35 × 5,22 m del plano de cargas, pero cuerpos y auxiliares del detalle de abril sobresalen de esa referencia, hasta aproximadamente 1,048 m por el extremo sur y 0,246 m por el lado oeste. Extensión geométrica resultante: 2,595899 × 6,268101 × 3,38 m, derivada y pendiente de coordinación entre revisiones. Permanecen dentro de la cabina acústica. Compatibilidad de revisión pendiente de fabricante.","Todas las alturas parciales son hipótesis de visualización; solo la altura total de 3,38 m está acotada.","Las regiones del dibujo se usan como envolventes de cuerpos; la identificación funcional y la cota Z de cada pieza requieren verificación.","Pequeños taladros, tornillería y detalles interiores de las regiones no se extruyen como vacíos de fabricación.","El bastidor documentado mide 2,35 × 5,22 m. Los accesorios del detalle de abril sobresalen; el conjunto refinado ocupa aproximadamente 2,596 × 6,268 m en ejes del fabricante, pendiente de coordinación entre revisiones."]; Dimensión X local del bastidor documentado (m): 2.35; Dimensión Y local del bastidor documentado (m): 5.22; Alcance de dimensiones X e Y originales: Bastidor de referencia de agosto; el detalle de accesorios de abril tiene mayor extensión.; Extensión X del conjunto refinado en ejes del fabricante (m): 2.5959; Extensión Y del conjunto refinado en ejes del fabricante (m): 6.2681; Nivel relativo de apoyo documentado (m): 0.4; Fuente del nivel de apoyo: {"documentId":"LHD2609-JG00100-20260904","title":"Cimentaciones y pedestales de equipos · revisión recibida 04/09/2026","date":"2026-09-04","sheet":"1 / 1-1","sourceHandles":["28C35","28C38","28C3B","28C89"]}; Criterio de instalación: Nivel de apoyo relativo documentado. Se adopta el cero de proceso a 286,10 m solo para visualización; la equivalencia absoluta no está confirmada. No se añade un espesor de montaje sin cota del fabricante.; Componente: Carcasa principal · región CAD 1; Rol del componente: provisional_casing_region; Capa de visualización: Envolventes de equipos; Estado del material: unknown; Perfil visual del material: equipment_light_gray; Fuente del componente: {"documentId":"EQ-IMPLANTACION-20260430","title":"Plano del fabricante: implantación de equipos","sheet":"LHD2609-GD01000 · espacio modelo","date":"2026-04-30","componentSourceHandles":["732E7","73405","73406","73407","7340A","73441"]}; Criterio de partición: Submalla de triángulos existentes; no hay nueva posición ni nuevas caras.; Criterio de las dimensiones: Cotas globales del conjunto conservadas aparte; las dimensiones de esta ficha son de la submalla.; Relación con cimentaciones: Coordinación del conjunto padre; anclaje directo individual no acreditado.; Aplicabilidad de las mediciones: Superficie y volumen geométricos brutos; no constituyen cantidades netas de obra, material o fabricación.; Capa BIM: Envolventes de equipos; Acabado de visualización: Equipo · gris claro provisional; Estado del acabado: provisional; Categoria: Componente de equipo · envolvente exterior; ClaseIFC: IfcCompressor; EstadoDeInformacion: provisional; DocumentoFuente: {"documentId":"EQ-IMPLANTACION-20260430","title":"Plano del fabricante: implantación de equipos","sheet":"LHD2609-GD01000 · espacio modelo","date":"2026-04-30","componentSourceHandles":["732E7","73405","73406","73407","7340A","73441"]}; IncidenciasPendientes: ["Componente separado de una reconstrucción documental del conjunto. Las alturas y detalles parciales conservan las limitaciones del fabricante registradas en parentEquipmentIssues.","Esta representación exterior no crea una chapa hueca ni añade componentes internos no documentados.","La pertenencia al conjunto no demuestra apoyo o anclaje directo a la cimentación."]; UsoDeLasMagnitudes: Geometría de coordinación. Los volúmenes de referencia y subcomponentes no son cantidades de material ni componentes de fabricación certificados.
JH_EvidenciaDeMaterial - name: No especificado; source: Sin especificación de material en la documentación revisada; status: unknown
JH_DetalleGeometrico - source: {"documentId":"EQ-IMPLANTACION-20260430","title":"Plano del fabricante: implantación de equipos","sheet":"LHD2609-GD01000 · espacio modelo","date":"2026-04-30","componentSourceHandles":["732E7","73405","73406","73407","7340A","73441"]}; heightSource: {"documentId":"EQ-CARGAS-20260825","title":"Plano del fabricante: cargas de equipos","sheet":"Espacio modelo","date":"2026-08-25"}; revision: Detalle en planta de 2026-04-30 coordinado de forma preliminar con envolventes y alturas de 2026-08-25; horizontalStatus: derivado; verticalRule: Altura total documentada: 3,38 m. Plataforma gráfica de 0,15 m; los cuerpos extraídos de la planta reciben alturas provisionales entre 1,00 y 3,38 m, detalladas por subvolumen. No se dispone de alzado acotado de cada componente.; status: Submalla exacta; interpretación funcional y cotas parciales provisionales.; unconfirmedDimensions: ["Todas las alturas parciales son hipótesis de visualización; solo la altura total de 3,38 m está acotada.","Las regiones del dibujo se usan como envolventes de cuerpos; la identificación funcional y la cota Z de cada pieza requieren verificación.","Pequeños taladros, tornillería y detalles interiores de las regiones no se extruyen como vacíos de fabricación."]; issues: ["El bastidor CAD coincide con la referencia de 2,35 × 5,22 m del plano de cargas, pero cuerpos y auxiliares del detalle de abril sobresalen de esa referencia, hasta aproximadamente 1,048 m por el extremo sur y 0,246 m por el lado oeste. Extensión geométrica resultante: 2,595899 × 6,268101 × 3,38 m, derivada y pendiente de coordinación entre revisiones. Permanecen dentro de la cabina acústica. Compatibilidad de revisión pendiente de fabricante."]; material: No especificado; quantityUse: Magnitudes de la geometría representada; no son cantidades de material, obra, compra, capacidad útil ni fabricación. En geometrías compuestas se suman superficies y volúmenes de partes y pueden existir solapes no depurados.; partsAreBOM: no; polygonizationToleranceM: 0.0001; outlineSimplificationToleranceM: 0.0005; partCount: 1; actualExtentManufacturerAxesM: [2.595899,6.268101,3.38]; sourceHandles: ["732E7","73405","73406","73407","7340A","73441"]
JH_CapaBIM - IdentificadorCapa: equipment_enclosures; NombreCapa: Envolventes de equipos; Funcion: Componente de equipo · envolvente exterior; VisibilidadInicial: yes
JH_AcabadoVisual - Perfil: equipment_light_gray; Acabado: Equipo · gris claro provisional; ColorRGB: [0.88,0.89,0.88]; Rugosidad: 0.45; Metallicidad: 0.28; Estado: provisional; Referencia: Referencia visual de fotografías públicas de Jinhong Gas / fabricante. Apariencia provisional para coordinación; fotografías oficiales pueden orientar el color, pero no acreditan el material, el acabado ni el equipo concreto.; Nota: La apariencia no certifica el material físico ni el acabado de fabricación.
Name | ElementosDeCimentacion = foundationIds | Extensión de la malla en X (m) = ExtensionX (m) | dimensions | positioning = PosicionYEstado | geometryMetrics | detailGeometry | parentEquipmentId = Identificador del fabricante o del modelo = Identificador del objeto = Identificador del elemento = Identificador del equipo padre = Identificador | parentEquipmentName = Equipo padre | parentEquipmentDimensions | assemblyBBox | assemblyGeometryMetrics | component | componentSeparation | assembly | visualizationIdentity | foundationRelationship | componentIds | childComponentIds | sourcePartIds | parentEquipmentProperties | Identificadores CAD del contorno (handles) | Identificador CAD de la cota de altura (handle) | Referencia dimensional del conjunto | sourceInsertHandle | sourcePartHandles | sourcePartId
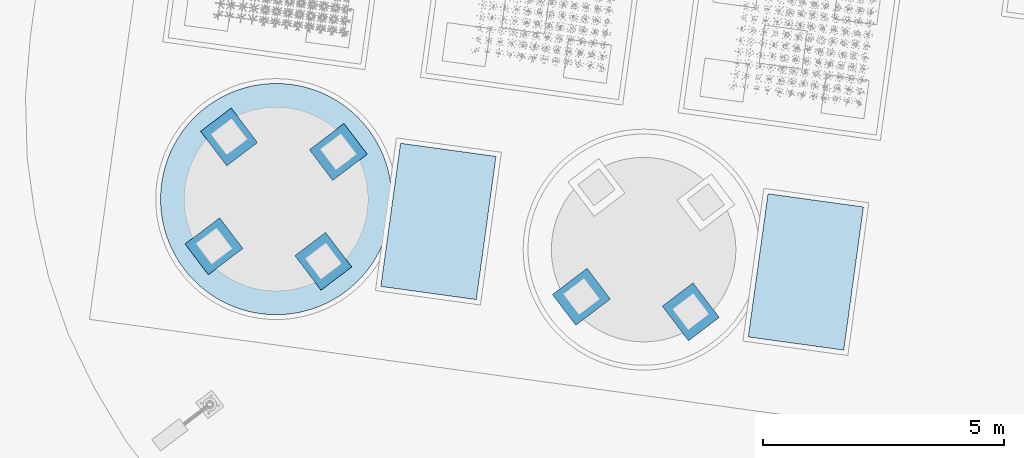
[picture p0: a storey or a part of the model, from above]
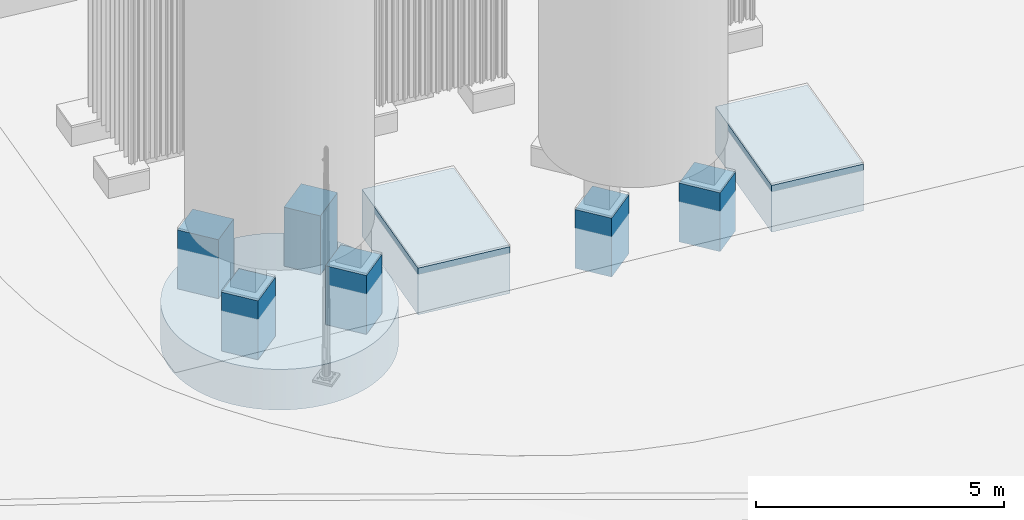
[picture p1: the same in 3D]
Properties of the parts of a building model (IFC4), part 57 of 134

# IfcCompressor: Envolvente de equipo (3)
Name | ElementosDeCimentacion = foundationIds | Extensión de la malla en X (m) = ExtensionX (m) | dimensions | positioning = PosicionYEstado | geometryMetrics | detailGeometry | parentEquipmentId = Identificador del fabricante o del modelo = Identificador del objeto = Identificador del elemento = Identificador del equipo padre = Identificador | parentEquipmentName = Equipo padre | parentEquipmentDimensions | assemblyBBox | assemblyGeometryMetrics | component | componentSeparation | assembly | visualizationIdentity | foundationRelationship | componentIds | childComponentIds | sourcePartIds | parentEquipmentProperties | Identificadores CAD del contorno (handles) | Identificador CAD de la cota de altura (handle) | Referencia dimensional del conjunto | sourceInsertHandle | sourcePartHandles | sourcePartId
Compresor de aire AC1001A · Carcasa principal · región CAD 1 | ["found_0904_b1416cc77686d5","found_0904_ee421d36db9553","found_0904_23cc68a21c3fa1","found_0904_bb30905ff8ceb7","found_0904_2eb7063ff00889"] | 0.965494 | {"documented":[{"label":"Referencia dimensional del conjunto","value":"Plano general y dimensiones globales de AC1001A; no se asignan esas dimensiones globales a este componente.","unit":"","source":"EQ-IMPLANTACION-20260430 · LHD2609-GD01000 · espacio modelo","status":"referencia_del_conjunto"}],"geometry":[{"label":"Extensión de la malla en X","value":0.9654939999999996,"unit":"m","source":"Geometría releída del IFC; datum absoluto de proceso provisional","status":"derivado"},{"label":"Extensión de la malla en Y","value":2.192864,"unit":"m","source":"Geometría releída del IFC; datum absoluto de proceso provisional","status":"derivado"},{"label":"Extensión de la malla en Z","value":2.3000000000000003,"unit":"m","source":"Geometría releída del IFC; datum absoluto de proceso provisional","status":"derivado"},{"label":"Cota inferior de visualización","value":286.65,"unit":"m","source":"Geometría releída del IFC; datum absoluto de proceso provisional","status":"derivado"},{"label":"Cota superior de visualización","value":288.95,"unit":"m","source":"Geometría releída del IFC; datum absoluto de proceso provisional","status":"derivado"}],"notes":["Las dimensiones del equipo completo se conservan en parentEquipmentDimensions.","Las extensiones en X/Y son de los ejes del modelo y no sustituyen cotas locales de fabricación.","No se infieren espesores de chapa, tolerancias ni dimensiones de piezas a partir de la partición."]} | {"Estado de la planta":"Derivado del CAD y del giro de implantación","Nivel relativo del apoyo (m)":0.4,"Estado del nivel relativo":"Documentado en el plano de cimentaciones","Cero absoluto de visualización (m)":286.1,"Estado del cero absoluto":"Provisional","Cota del apoyo de visualización (m)":286.5,"Desplazamiento aplicado a la malla (m)":0.40000000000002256,"Criterio":"Nivel de apoyo relativo documentado. Se adopta el cero de proceso a 286,10 m solo para visualización; la equivalencia absoluta no está confirmada. No se añade un espesor de montaje sin cota del fabricante.","horizontalStatus":"derivado_del_conjunto","verticalStatus":"derivado_del_conjunto","coordinateSystem":"model_local_m","parentEquipmentId":"AC1001A","transformApplied":false,"note":"Coordenadas copiadas exactamente del equipo coordinado; no se ha movido, girado, elevado ni reescalado este componente.","foundationRelationship":"El apoyo y las cotas de instalación se documentan para el conjunto padre. Esta submalla no acredita un anclaje directo.","meshMinimumAbsoluteElevationM":286.65,"assemblyPlacementField":"parentEquipmentPositioning"} | {"boundingBoxM":{"min":[48.557326,71.129696,1.65],"max":[49.52282,73.32256,3.95]},"extentsM":[0.965494,2.192864,2.3],"meshSurfaceM2":15.939718,"meshVolumeM3":3.31696,"closedSolid":true,"basis":"Geometría de coordinación. Los volúmenes de referencia y subcomponentes no son cantidades de material ni componentes de fabricación certificados."} | {"source":{"documentId":"EQ-IMPLANTACION-20260430","title":"Plano del fabricante: implantación de equipos","sheet":"LHD2609-GD01000 · espacio modelo","date":"2026-04-30","componentSourceHandles":["732E7","73405","73406","73407","7340A","73441"]},"heightSource":{"documentId":"EQ-CARGAS-20260825","title":"Plano del fabricante: cargas de equipos","sheet":"Espacio modelo","date":"2026-08-25"},"revision":"Detalle en planta de 2026-04-30 coordinado de forma preliminar con envolventes y alturas de 2026-08-25","horizontalStatus":"derivado","verticalRule":"Altura total documentada: 3,38 m. Plataforma gráfica de 0,15 m; los cuerpos extraídos de la planta reciben alturas provisionales entre 1,00 y 3,38 m, detalladas por subvolumen. No se dispone de alzado acotado de cada componente.","status":"Submalla exacta; interpretación funcional y cotas parciales provisionales.","unconfirmedDimensions":["Todas las alturas parciales son hipótesis de visualización; solo la altura total de 3,38 m está acotada.","Las regiones del dibujo se usan como envolventes de cuerpos; la identificación funcional y la cota Z de cada pieza requieren verificación.","Pequeños taladros, tornillería y detalles interiores de las regiones no se extruyen como vacíos de fabricación."],"issues":["El bastidor CAD coincide con la referencia de 2,35 × 5,22 m del plano de cargas, pero cuerpos y auxiliares del detalle de abril sobresalen de esa referencia, hasta aproximadamente 1,048 m por el extremo sur y 0,246 m por el lado oeste. Extensión geométrica resultante: 2,595899 × 6,268101 × 3,38 m, derivada y pendiente de coordinación entre revisiones. Permanecen dentro de la cabina acústica. Compatibilidad de revisión pendiente de fabricante."],"material":"No especificado","quantityUse":"Magnitudes de la geometría representada; no son cantidades de material, obra, compra, capacidad útil ni fabricación. En geometrías compuestas se suman superficies y volúmenes de partes y pueden existir solapes no depurados.","partsAreBOM":false,"sourceInsertHandle":"835CE","polygonizationToleranceM":0.0001,"outlineSimplificationToleranceM":0.0005,"partCount":1,"sourcePartHandles":[{"partId":"AC1001A--base","sourceHandles":["3F3"]},{"partId":"AC1001A--cad-region-001","sourceHandles":["732E7","73405","73406","73407","7340A","73441"]},{"partId":"AC1001A--cad-region-002","sourceHandles":["7133E","7133F","732E7","73405","73406","73408","73409","73441"]},{"partId":"AC1001A--cad-region-003","sourceHandles":["71316","71317","72C0A","72C15","72C2A","72C3B","72C3F","72C41","72C42","72C44","72C45","72C46","72C47","72C48","72C49","72C4A","72C4B","72C4C","72C4D","72C4E","72C4F","72C50","72C51","72C52","72C53","72C54","72C55","72C56","72C57","72C58","72C59","72C5A","72C5B","72C5C","72C5D","72C5E","72C5F","72C60","72C61","72C62","72C63","72C64","72C65","72C66","72C67","72C68","72C69","72C6A","72C6B","72C6C","72C6D","72C6E","72C6F","72C70","72C71","72C72","72C73","72C74","72C75","72C76","72C77","72C78","72C79","72C7A","72C7B","72C7C","72C7D","72C7E","72C7F","72C80","72C84","72C88","72C89","72C9E","72CA1","72CA4","72CA7","72CAA","72CAD","72CB0","72CB3","72CB6","72CB9","72CBC","72CBF","72CC2","72CC5","72CC8","72CCB","72CCE","72CD1","72CD4","72CD7","72CDA","72CDC","72CDD","72CE5","72CE6","72CE7","72CE8","72CE9","72CEA","72CEB","72CEC","72CED","72CEE","72CEF","72CF0","72CF1","72CF2","72CF3","72CF4","72CF5","72CF6","72CF7","72CF8","72CF9","72CFA","72CFB","72CFC","72CFD","72CFE","72CFF","72D00","72D01","72D02","72D03","72D04","72D05","72D06","72D07","72D08","72D0A","72D0B","72D0C","72D0D","72D0E","72D0F","72D10","72D11","72D13","72D14","72D15","72D16","72D17","72D18","72D19","72D1A","72D1B","72D1C","72D1D","72D1E","72D1F","72D20","72D21","72D22","72D23","72D24","72D26","72D27","72D28","72D29","72D2A","72D2B","72D2C","72D2D","72D2E","72D31","72D33","72D51","72D52","72D65","72D66","72D67","72D68","72D69","72D6A","72D6B","72D6C","72D6D","72D6E","72D6F","72D70","72D71","72D72","72D73","72D74","72D75","72D76","72D77","72D78","72D79","72D7A","72D7B","72D7C","72D7D","72D7E","72D7F","72D80","72D81","72D82","72D83","72D84","72D85","72D86","72D87","72D88","72D89","72D8A","72D8B","72D8C","72D8D","72D8E","72D8F","72D90","72D91","72D92","72D93","72D94","72D95","72D96","72D97","72D98","72D99","72D9A","72D9B","72D9C","72D9D","72D9E","72D9F","72DA0","72DA1","72DA2","72DA3","72DA4","72DA5","72DA6","72DA7","72DA8","72DA9","72DAA","72DAB","72DAC","72DAD","72DAE","72DAF","72DB0","72DB1","72DB2","72DB3","72DB4","72DB5","72DB6","72DB7","72DB8","72DB9","72DBA","72DBB","72DBC","72DBD","72DBE","72DBF","72DC0","72DC1","72DC2","72DC3","72DC4","72DC5","72DC6","72DC7","72DC8","72DC9","72DCA","72DCB","72DCC","72DCD","72DCE","72DCF","72DD0","72DD1","72DD2","72DD3","72DD4","72DD5","72DD6","72DD7","72DD8","72DD9","72DDA","72DDB","72DDC","72DDD","72DDE","72DDF","72DE0","72DE1","72DE2","72DE3","72DE4","72DE5","72DE6","72DE7","72DE8","72DE9","72DEA","72DEB","72DEC","72DED","72DEE","72DEF","72DF0","72DF1","72DF2","72DF3","72DF4","72DF5","72DF6","72DF7","72DF8","72DF9","72DFA","72DFB","72DFC","72DFD","72DFE","72DFF","72E00","72E01","72E02","72E03","72E04","72E05","72E06","72E07","72E08","72E09","72E0A","72E0B","72E0C","72E0D","72E0E","72E0F","72E10","72E11","72E12","72E13","72E14","72E15","72E16","72E17","72E18","72E19","72E1A","72E1B","72E1C","72E1D","72E1E","72E1F","72E20","72E21","72E22","72E23","72E24","72E25","72E26","72E27","72E28","72E29","72E2A","72E2B","72E2C","72E2D","72E2E","72E2F","72E30","72E31","72E32","72E33","72E34","72E35","72E36","72E37","72E38","72E39","72E3A","72E3B","72E3C","72E3D","72E3E","72E3F","72E40","72E41","72E42","72E43","72E44","72E45","72E46","72E47","72E48","72E49","72E4A","72E4B","72E4C","72E4D","72E4E","72E4F","72E50","72E51","72E52","72E53","72E54","72E55","72E56","72E57","72E58","72E59","72E5A","72E5B","72E5C","72E5D","72E5E","72E5F","72E60","72E61","72E62","72E63","72E64","72E65","72E66","72E67","72E68","72E69","72E6A","72E6B","72E6C","72E6D","72E6E","72E6F","72E70","72E71","72E72","72E73","72E74","72E75","72E76","72E77","72E78","72E79","72E7A","72E7B","72E7E","72E7F","72E85","72E86","72E87","72E88","72E8D","72E8E","72E8F","72E90","72E92","72E93","72E99","72EBB","72EBC","72EBD","72EBE","72EBF","72EC0","72EC1","72EC2","72EC4","72EC5","72EC6","72EC7","72EC8","72EC9","72ECA","72ECB","72ECC","72ECD","72ECE","72ED0","72ED1","72ED2","72ED3","72ED4","72ED5","72ED6","72ED7","72ED8","72ED9","72EDA","72F07","72F08","72F09","72F0A","72F0C"]},{"partId":"AC1001A--cad-region-004","sourceHandles":["73405","73406","73407"]},{"partId":"AC1001A--cad-region-005","sourceHandles":["71365","7166E","7167F","71926","71928","721E1","721E4","724C3","724CC","724CE","724D9","72513","7252D","7252E","7252F","72531","729A2","729A3","729A5","729A8","72C01","72C02","7302A","73042","73078","730A8","730FF","73101","73103","73105","73106","73107","73110","73112","73114","73115","732E7","73401","73404","73405","73406","73407"]},{"partId":"AC1001A--cad-region-006","sourceHandles":["732EB","732EC","732ED","732EE","732EF","732F0","732F1","732F2","73302","73305","73306","73307","73308","7330A","7330B","7330D","7330E","7330F","73310","73311","73312","73313","73322","73325","73326","73327","73328","73329","7332C","7332D","7332E","7332F","73332","73333","73334","73335","73337","73338","73339","7333E","7333F","73340","73341","73349","7334A","7334B","7334D","7334E","7334F","73350","73351","73352","73353","73354","73355","73356","73357","73359","7335A","7335B","7335D","73364","73365","73366","73367","73368","73369","7336A","7336B","7336C","7336D","7336E","7336F","73370","73372","73377","73378","7337C","7337D","7337E","73390","73398","73399","733A0","733A2","733A4","733A9","733AB","733AC","733AD","733B1","733B2","733B6","733B8","733B9","733BA","733C4","733CC","733D8","733DE","733DF","733E7","733E8","733E9","733F0","73403","734A4","734A5","734A7","734A8","734A9","734AA","734AB","734AC","734AD","734AE","734AF","734B0"]},{"partId":"AC1001A--cad-region-007","sourceHandles":["729DA","729DB","72A33","72A34","72A35","72A3C","72A45","72A46","72A47","72A48","72A49","72A4E","72A4F","72A50"]},{"partId":"AC1001A--cad-region-008","sourceHandles":["7101E","7101F","71020","71021","71022","710E1","710E2","712F6","712F7","712F8","73403"]},{"partId":"AC1001A--cad-region-009","sourceHandles":["72546","72549","725A4","725A5","725A7","72763","7276F","72777","72789","72794","727AC","727AE","727AF","727B0","727B1","727B2","733F4","733F5","733F6","733FB","733FC","733FD"]},{"partId":"AC1001A--cad-region-011","sourceHandles":["713B1","713E3","713E4","713F7","71621","71623","71670","71671","71676","7167C","7167D","7177D","7177E","71784","71785","72989","72994","72995","72998","7299A","7299E","729A0","729BE","729BF","729C1","729C3","72F34","72F35","72F38","73103","73104","73105","73108","7310A","732E7","73430"]},{"partId":"AC1001A--cad-region-012","sourceHandles":["71A33","73144","73147","73162","73163","73175"]},{"partId":"AC1001A--cad-region-013","sourceHandles":["7103B","7103F","71040","71041","71042","71045","71046","71050","71075","71076","7109E","710A0","710A4","710A5","710A6","710A7","710A8","710B1","710B2","710B3","710B4","710B5","710B6","710B7","710B8","710BA","710BB","710BC","710BD","710C1","710C4","710C5","710C6","710CC","710CE","710D3","710D7","710D8","710D9","710DB","710DD","710E4","710E5","710EB","710F0","710F3","710F8","710FC","710FE","7110F","71111","71116","71142","71276","71285","7129B","712A1","712A3","712A9","712AC","71302","71306","7130B","7130F"]},{"partId":"AC1001A--cad-region-014","sourceHandles":["71428","71618","7189D","7189E","718A2","718A4","718A7","71930","71931","7193B","7193D","72411","7241B","7241C","7241D","72420","72422","72423","72424","72513","729B9","729BB","729BC","72F28","72F2F","72F39","72F3E","72F40","72F54","72F5B","72F5F","72F60","72F63","72F69","72F70","72F73","72F75","72F78","72F79","72F7A","72F7D","72F80","72F84","72F86","72F88","72F89","72F8A","72F8B","72F8C","72F8D","72F8E","72F8F","72F90","72F92","72F9B","72F9D","72F9E","72FB1","72FB2","72FB6","72FB8","72FC0","72FC2","72FCB","72FCD","72FD6","72FD7","72FD8","72FD9","72FDA","72FDB","72FDC","72FDE","72FEC","72FED","72FEE","72FEF","72FF0","72FF1","72FF2","72FF3","72FF4","72FF5","72FF6","72FF7","72FFA","72FFB","72FFC","72FFE","72FFF","73000","73001","73004","73005","73008","73009","7300A","7300B","7300E","7300F","73010","73012","73013","73014","73015","73018","73019","7301C","7301D","7301E","7301F","73022","73023","73024","7302A","7302B","7302C","7302D","73030","73035","73036","7303A","7303C","7303D","7303E","7303F","73040","73041","73042","73047","73048","73049","7304B","7304C","73058","7305C","7305D","7305E","73062","73066","73067","73068","73069","7306A","7306C","7306D","7306F","73070","73071","73072","73073","73074","730A9","730AB","730AC","730AD","730AE","730AF","730B0","730B1","730B2","730B3","730B4","730B5","730B8","730BC","730BD","730BE","730BF","730C0","730C1","730C2","730C3","730C4","730C5","730C7","730C9","730CB","730CC","730CD","730CF","730D2","730D5","730D8","730D9","730DA","730DC","730DF","730E2","730E8","730EB","730EF","730F0","730F1","730F4","730F6","730F7","730F8","730FA","7310B","732E7"]},{"partId":"AC1001A--cad-region-015","sourceHandles":["71619","71674","71675","71679","7167A","71780","71781","718A0","718A5","718A9","718AC","7251F","72523","72524","72F34","72F36","72F37","72F38","72F3C","72F41","72F51","72F55","72F5C","72F61","72F65","72F68","72F6A","72F6F","72F72","72F74","72F7B","72F7C","72F7E","72F83","72F85","72F87","72F8B","72F98","72F99","72F9A","72FD3","72FD4","73027","73028","73029","7302A","7302E","7302F","73031","73037","7303C","7303D","7303F","73076","73077","73078","73079","7307A","7307B","7307C","7307D","7307E","73085","73086","73089","7308A","73091","73092","73094","73095","73096","7309A","7309B","7309C","7309E","7309F","730A0","730A2","730A5","730A6","730A7","730A8","730AA","730E6","730E7","730EC","730ED","730EE","730F2","730FC","732E7","73468","734A1"]},{"partId":"AC1001A--cad-region-017","sourceHandles":["7134C","71A0B","71A0C","71A0F","71A10","71A11","71A17","71A68","72D35","72D38"]},{"partId":"AC1001A--cad-region-018","sourceHandles":["7134C","72C0A","72D2E","72D32","72D34","72D35","72D36"]},{"partId":"AC1001A--cad-region-019","sourceHandles":["71A0C","71A0E","72D2E","72D34","72D35","72D38"]},{"partId":"AC1001A--cad-region-020","sourceHandles":["7134D","71625","71657","71658","71659","7165A","7165C","7165D","7165F","71684","71711","71712","71713","71714","7171D","7171E","7171F","71720","71721","71722","71723","71724","71725","71727","71728","71729","7172A","7172B","7172F","71731","71732","71733","7173D","7173E","7173F","71740","717D3","717FA","717FC","71907","71981","71A0F","71A13","71A3C"]},{"partId":"AC1001A--cad-region-024","sourceHandles":["7134F","71355","71DB1","72F08","72F0B","72F10","72F11"]},{"partId":"AC1001A--cad-region-025","sourceHandles":["71621","71642","7164D","71969","7196A","7196F","71974","71976","73116","73117","73118","73119","7311A","7311B","7311C","7311D","7311E","7311F","73120","73121","73122","73124","73125","73128","7312E","73138","73139","73181","73183","73186","7318B","73195","73197","73199","7319A","731A1","731A7","7340D","7340F","73419","7341B","73420","73422","7342C","7342E"]},{"partId":"AC1001A--cad-region-026","sourceHandles":["71A59","71DB1","71DB2","71DB5","72F0D","72F10","72F11"]},{"partId":"AC1001A--cad-region-027","sourceHandles":["71743","71744","71745","71746","71749","71753","71754","7175F","71760","717A8","717AB","717F4","7181D","7181E","71828","71829","7182F","71832","71833","718C5","718C9","719CA","719CC","71A2F","71A44","71DB9","73148","73153","73154","7344E"]},{"partId":"AC1001A--cad-region-028","sourceHandles":["717FF","71801","71803","71805","71A46","71A58","71A59","71BA6","71BA7","71DB1","71DB2","71DB4","71DB5","72EE3","72EE5","72EE6","72EEA","72EEB","72EEF","72EF0","72EF3","72EF4","72EF6","72F00","72F01","72F02","72F0D","72F0E","72F0F","72F11","73157","73158","73159","7315A","7315B","7315C","731BD","731C4","731C5","731C7","731CB","731CC","731CD","731D9","731DE","731DF","731E0","731E1","731E2","731E3","731E4","731E5","731E6","731EE","731EF","731F0","731F1","731F2","731F3","731F4","731F5","731F6","731F7","731F9","731FF","73200","73201","73202","73204","73205","73206","73207","7320B","7320D","7320E","7320F","73210","73212","7321C","7321D"]},{"partId":"AC1001A--cad-region-029","sourceHandles":["717F2","71A09","71A0B","71A11","71A3C","71A3F","71A40","71A41","71A42","71A43","71A5B","71DCB","71E9B","728D5","728E4","728E5","728F2","72D37","72D38","72D3F","72D40","72D41","72D42","72E80","72E81"]},{"partId":"AC1001A--cad-region-035","sourceHandles":["7134F","719FC","719FD","719FE","71A18","71A1A","71A45","71A46","71A4D","71A58","71A59","71DB1","72F11"]}],"actualExtentManufacturerAxesM":[2.595899,6.268101,3.38],"sourcePartId":"AC1001A--cad-region-001","sourceHandles":["732E7","73405","73406","73407","7340A","73441"]} | AC1001A | Compresor de aire AC1001A | {"documented":[{"label":"Dimensión X local del bastidor de referencia CAD","value":2.35,"unit":"m","source":"EQ-CARGAS-20260825 · contorno CAD · handles 3F3","status":"derivado"},{"label":"Dimensión Y local del bastidor de referencia CAD","value":5.22,"unit":"m","source":"EQ-CARGAS-20260825 · contorno CAD · handles 3F3","status":"derivado"},{"label":"Altura acotada","value":3.38,"unit":"m","source":"EQ-CARGAS-20260825 · handle 52E","status":"documentado"},{"label":"Cota relativa de la superficie de apoyo","value":0.4,"unit":"m","source":"LHD2609-JG00100-20260904 · sección 1 / 1-1 · 28C35, 28C38, 28C3B, 28C89","status":"documentado"}],"geometry":[{"label":"Extensión de la malla en X","value":3.1775829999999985,"unit":"m","source":"Geometría releída del IFC; datum absoluto de proceso provisional","status":"derivado"},{"label":"Extensión de la malla en Y","value":6.404527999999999,"unit":"m","source":"Geometría releída del IFC; datum absoluto de proceso provisional","status":"derivado"},{"label":"Extensión de la malla en Z","value":3.3800000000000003,"unit":"m","source":"Geometría releída del IFC; datum absoluto de proceso provisional","status":"derivado"},{"label":"Cota inferior de visualización","value":286.5,"unit":"m","source":"Geometría releída del IFC; datum absoluto de proceso provisional","status":"derivado"},{"label":"Cota superior de visualización","value":289.88,"unit":"m","source":"Geometría releída del IFC; datum absoluto de proceso provisional","status":"derivado"}],"notes":["Las extensiones de la malla se miden en los ejes del proyecto tras el giro de implantación; no sustituyen las dimensiones locales del fabricante.","La envolvente, su volumen y los espesores de visualización no son volúmenes de material ni cantidades de compra, construcción o fabricación.","Las dimensiones documentadas distinguen cotas explícitas y medidas extraídas de contornos CAD; las dimensiones geométricas describen únicamente la malla publicada.","Las extensiones de la malla refinada y las dimensiones documentadas del contorno o bastidor tienen distinto alcance; las cotas parciales del detalle son provisionales."]} | {"min":[48.139687,70.121823,1.5],"max":[51.31727,76.526351,4.88]} | {"boundingBoxM":{"min":[48.139687,70.121823,1.5],"max":[51.31727,76.526351,4.88]},"extentsM":[3.1775829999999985,6.404527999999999,3.38],"meshSurfaceM2":165.1982435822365,"meshVolumeM3":20.17009895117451,"closedSolid":true,"windingConsistent":true,"basis":"Submalla exacta de los triángulos del modelo IFC coordinado; separación de componentes sin transformación ni retesselación."} | {"id":"AC1001A","sourcePartId":"AC1001A--cad-region-001","name":"Carcasa principal · región CAD 1","role":"provisional_casing_region","classificationStatus":"provisional","classificationBasis":"Rol del subvolumen gráfico según el activo de detalle; identidad de fabricación no confirmada.","parentEquipmentId":"AC1001A","parentEquipmentGuid":"1ZhOcwnsbMzxhqtlvKa3pG","isAssemblyIdentityCarrier":true,"sourceFaceRange":[12,36],"sourceCurrentFaceIndices":[12,13,14,15,16,17,18,19,20,21,22,23,24,25,26,27,28,29,30,31,32,33,34,35],"sourceMeshSha256":"7b60c904c9d84d22fded9be34af09a09a9c198ec8e75e61902634d5e4064c761","sourceVertexIndices":[8,9,10,11,12,13,14,15,16,17,18,19,20,21],"separationMethod":"Partición exacta de triángulos existentes; coordenadas y orientación de caras conservadas.","quantityUse":"Magnitudes geométricas del subvolumen; no son cantidades netas de material, fabricación, suministro o capacidad."} | {"status":"componente_independiente","note":"Objeto independiente seleccionable. Las caras se asignan una sola vez entre todos los componentes del conjunto.","parentEquipmentId":"AC1001A","isAssemblyIdentityCarrier":true,"relatedEnclosureIds":["AC-ENC-1"]} | {"id":"AC1001A","name":"Compresor de aire AC1001A","relationship":"identity_carrier_with_child_components","parentShapeMeaning":"La forma del objeto que conserva el ID del equipo es únicamente su componente principal; el conjunto completo requiere sus hijos."} | {"elementId":"AC1001A","ifcGuid":"1ZhOcwnsbMzxhqtlvKa3pG","ifcClass":"IfcCompressor","buildingId":"process_plant","buildingName":"Planta de proceso","sourceDocumentId":"EQ-IMPLANTACION-20260430","sourceRepresentationKind":"equipmentComponent"} | {"kind":"assembly_documentation","parentEquipmentId":"AC1001A","directAnchorageVerified":false,"note":"La relación del conjunto con cimentaciones se conserva en el objeto que mantiene el ID del equipo; no se atribuye fijación directa a cada subcomponente."} | ["AC1001A--base","AC1001A","AC1001A--cad-region-002","AC1001A--cad-region-003","AC1001A--cad-region-004","AC1001A--cad-region-005","AC1001A--cad-region-006","AC1001A--cad-region-007","AC1001A--cad-region-008","AC1001A--cad-region-009","AC1001A--cad-region-011","AC1001A--cad-region-012","AC1001A--cad-region-013","AC1001A--cad-region-014","AC1001A--cad-region-015","AC1001A--cad-region-017","AC1001A--cad-region-018","AC1001A--cad-region-019","AC1001A--cad-region-020","AC1001A--cad-region-024","AC1001A--cad-region-025","AC1001A--cad-region-026","AC1001A--cad-region-027","AC1001A--cad-region-028","AC1001A--cad-region-029","AC1001A--cad-region-035"] | ["AC1001A--base","AC1001A--cad-region-002","AC1001A--cad-region-003","AC1001A--cad-region-004","AC1001A--cad-region-005","AC1001A--cad-region-006","AC1001A--cad-region-007","AC1001A--cad-region-008","AC1001A--cad-region-009","AC1001A--cad-region-011","AC1001A--cad-region-012","AC1001A--cad-region-013","AC1001A--cad-region-014","AC1001A--cad-region-015","AC1001A--cad-region-017","AC1001A--cad-region-018","AC1001A--cad-region-019","AC1001A--cad-region-020","AC1001A--cad-region-024","AC1001A--cad-region-025","AC1001A--cad-region-026","AC1001A--cad-region-027","AC1001A--cad-region-028","AC1001A--cad-region-029","AC1001A--cad-region-035"] | ["AC1001A--base","AC1001A--cad-region-001","AC1001A--cad-region-002","AC1001A--cad-region-003","AC1001A--cad-region-004","AC1001A--cad-region-005","AC1001A--cad-region-006","AC1001A--cad-region-007","AC1001A--cad-region-008","AC1001A--cad-region-009","AC1001A--cad-region-011","AC1001A--cad-region-012","AC1001A--cad-region-013","AC1001A--cad-region-014","AC1001A--cad-region-015","AC1001A--cad-region-017","AC1001A--cad-region-018","AC1001A--cad-region-019","AC1001A--cad-region-020","AC1001A--cad-region-024","AC1001A--cad-region-025","AC1001A--cad-region-026","AC1001A--cad-region-027","AC1001A--cad-region-028","AC1001A--cad-region-029","AC1001A--cad-region-035"] | {"Referencia en el plano del fabricante":"1","Identificador del fabricante o del modelo":"AC1001A","Documento de origen":"Plano del fabricante: cargas de equipos · 2026-08-25 · Espacio modelo; número de plano no identificado","Documento CAD derivado":"Conversión DXF del plano de cargas de equipos · 2026-08-25 · espacio modelo","Capa CAD de referencia":"Anotaciones y contornos de equipos","Identificadores CAD del contorno (handles)":"3F3","Identificador CAD de la cota de altura (handle)":"52E","Cota de altura del fabricante (traducción)":"Altura del equipo: 3.38m","Altura (m)":3.38,"Origen de las dimensiones":"Plano de cargas del fabricante de 2026-08-25: lectura directa del contorno CAD cerrado y de la cota de altura del equipo.","Grado de definición":"Planta derivada del CAD, altura total documentada y alturas parciales provisionales.","Alcance de la geometría":"Geometría compuesta con perfiles CAD y distribución vertical provisional; véase Detalle geométrico.","Origen de la posición":"Punto de referencia del fabricante: entidad CIRCLE, handle 98, en la esquina inferior izquierda de la zona de equipos. Los ejes X e Y son locales y se giran para su implantación UTM.","Hipótesis de modelado":"Nivel de apoyo relativo documentado. Se adopta el cero de proceso a 286,10 m solo para visualización; la equivalencia absoluta no está confirmada. No se añade un espesor de montaje sin cota del fabricante.","Observaciones":"Envolvente de la máquina interior contenida en la cabina acústica. Su superposición representa esa relación de contención; ambos grupos pueden visualizarse por separado.","Masa propia indicada (kg)":30000,"Dimensiones de la plataforma de equipos (m)":"27 × 57 m; dimensiones acotadas en el plano general.","Implantación de la plataforma de equipos":"El punto de referencia del fabricante coincide con la esquina suroeste de la zona de equipos. Giro local de −7,82824° para la implantación en coordenadas UTM.","Estado de la cota de instalación":"Nivel de apoyo relativo documentado. Se adopta el cero de proceso a 286,10 m solo para visualización; la equivalencia absoluta no está confirmada. No se añade un espesor de montaje sin cota del fabricante.","Convención de coordenadas":"Coordenadas locales del proyecto en metros. Añadir (729400, 4301550, 285) para recuperar las coordenadas UTM y las cotas del plano.","Identificador del objeto":"AC1001A","Disciplina":"Equipos","Clase IFC":"IfcCompressor","Fase del modelo":"Revisión de la zona de separación de aire · septiembre de 2026","Representación geométrica IFC":"Sólido IFC4 mediante malla triangular cerrada","Aplicabilidad a mediciones":"Magnitudes de la geometría representada; no son cantidades de material, obra, compra, capacidad útil ni fabricación. En geometrías compuestas se suman superficies y volúmenes de partes y pueden existir solapes no depurados.","Material":"No especificado","Estado de la información":"provisional","Detalle geométrico":"derivado","Incidencias del detalle":["Nivel de apoyo relativo documentado. Se adopta el cero de proceso a 286,10 m solo para visualización; la equivalencia absoluta no está confirmada. No se añade un espesor de montaje sin cota del fabricante.","La máquina está contenida en la envolvente de la cabina acústica; su superposición no acredita una interferencia física.","El bastidor CAD coincide con la referencia de 2,35 × 5,22 m del plano de cargas, pero cuerpos y auxiliares del detalle de abril sobresalen de esa referencia, hasta aproximadamente 1,048 m por el extremo sur y 0,246 m por el lado oeste. Extensión geométrica resultante: 2,595899 × 6,268101 × 3,38 m, derivada y pendiente de coordinación entre revisiones. Permanecen dentro de la cabina acústica. Compatibilidad de revisión pendiente de fabricante.","Todas las alturas parciales son hipótesis de visualización; solo la altura total de 3,38 m está acotada.","Las regiones del dibujo se usan como envolventes de cuerpos; la identificación funcional y la cota Z de cada pieza requieren verificación.","Pequeños taladros, tornillería y detalles interiores de las regiones no se extruyen como vacíos de fabricación.","El bastidor documentado mide 2,35 × 5,22 m. Los accesorios del detalle de abril sobresalen; el conjunto refinado ocupa aproximadamente 2,596 × 6,268 m en ejes del fabricante, pendiente de coordinación entre revisiones."],"Dimensión X local del bastidor documentado (m)":2.35,"Dimensión Y local del bastidor documentado (m)":5.22,"Alcance de dimensiones X e Y originales":"Bastidor de referencia de agosto; el detalle de accesorios de abril tiene mayor extensión.","Extensión X del conjunto refinado en ejes del fabricante (m)":2.595899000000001,"Extensión Y del conjunto refinado en ejes del fabricante (m)":6.268100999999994,"Nivel relativo de apoyo documentado (m)":0.4,"Fuente del nivel de apoyo":{"documentId":"LHD2609-JG00100-20260904","title":"Cimentaciones y pedestales de equipos · revisión recibida 04/09/2026","date":"2026-09-04","sheet":"1 / 1-1","sourceHandles":["28C35","28C38","28C3B","28C89"]},"Criterio de instalación":"Nivel de apoyo relativo documentado. Se adopta el cero de proceso a 286,10 m solo para visualización; la equivalencia absoluta no está confirmada. No se añade un espesor de montaje sin cota del fabricante."} | 3F3 | 52E | Plano general y dimensiones globales de AC1001A; no se asignan esas dimensiones globales a este componente. | 835CE | [{"partId":"AC1001A--base","sourceHandles":["3F3"]},{"partId":"AC1001A--cad-region-001","sourceHandles":["732E7","73405","73406","73407","7340A","73441"]},{"partId":"AC1001A--cad-region-002","sourceHandles":["7133E","7133F","732E7","73405","73406","73408","73409","73441"]},{"partId":"AC1001A--cad-region-003","sourceHandles":["71316","71317","72C0A","72C15","72C2A","72C3B","72C3F","72C41","72C42","72C44","72C45","72C46","72C47","72C48","72C49","72C4A","72C4B","72C4C","72C4D","72C4E","72C4F","72C50","72C51","72C52","72C53","72C54","72C55","72C56","72C57","72C58","72C59","72C5A","72C5B","72C5C","72C5D","72C5E","72C5F","72C60","72C61","72C62","72C63","72C64","72C65","72C66","72C67","72C68","72C69","72C6A","72C6B","72C6C","72C6D","72C6E","72C6F","72C70","72C71","72C72","72C73","72C74","72C75","72C76","72C77","72C78","72C79","72C7A","72C7B","72C7C","72C7D","72C7E","72C7F","72C80","72C84","72C88","72C89","72C9E","72CA1","72CA4","72CA7","72CAA","72CAD","72CB0","72CB3","72CB6","72CB9","72CBC","72CBF","72CC2","72CC5","72CC8","72CCB","72CCE","72CD1","72CD4","72CD7","72CDA","72CDC","72CDD","72CE5","72CE6","72CE7","72CE8","72CE9","72CEA","72CEB","72CEC","72CED","72CEE","72CEF","72CF0","72CF1","72CF2","72CF3","72CF4","72CF5","72CF6","72CF7","72CF8","72CF9","72CFA","72CFB","72CFC","72CFD","72CFE","72CFF","72D00","72D01","72D02","72D03","72D04","72D05","72D06","72D07","72D08","72D0A","72D0B","72D0C","72D0D","72D0E","72D0F","72D10","72D11","72D13","72D14","72D15","72D16","72D17","72D18","72D19","72D1A","72D1B","72D1C","72D1D","72D1E","72D1F","72D20","72D21","72D22","72D23","72D24","72D26","72D27","72D28","72D29","72D2A","72D2B","72D2C","72D2D","72D2E","72D31","72D33","72D51","72D52","72D65","72D66","72D67","72D68","72D69","72D6A","72D6B","72D6C","72D6D","72D6E","72D6F","72D70","72D71","72D72","72D73","72D74","72D75","72D76","72D77","72D78","72D79","72D7A","72D7B","72D7C","72D7D","72D7E","72D7F","72D80","72D81","72D82","72D83","72D84","72D85","72D86","72D87","72D88","72D89","72D8A","72D8B","72D8C","72D8D","72D8E","72D8F","72D90","72D91","72D92","72D93","72D94","72D95","72D96","72D97","72D98","72D99","72D9A","72D9B","72D9C","72D9D","72D9E","72D9F","72DA0","72DA1","72DA2","72DA3","72DA4","72DA5","72DA6","72DA7","72DA8","72DA9","72DAA","72DAB","72DAC","72DAD","72DAE","72DAF","72DB0","72DB1","72DB2","72DB3","72DB4","72DB5","72DB6","72DB7","72DB8","72DB9","72DBA","72DBB","72DBC","72DBD","72DBE","72DBF","72DC0","72DC1","72DC2","72DC3","72DC4","72DC5","72DC6","72DC7","72DC8","72DC9","72DCA","72DCB","72DCC","72DCD","72DCE","72DCF","72DD0","72DD1","72DD2","72DD3","72DD4","72DD5","72DD6","72DD7","72DD8","72DD9","72DDA","72DDB","72DDC","72DDD","72DDE","72DDF","72DE0","72DE1","72DE2","72DE3","72DE4","72DE5","72DE6","72DE7","72DE8","72DE9","72DEA","72DEB","72DEC","72DED","72DEE","72DEF","72DF0","72DF1","72DF2","72DF3","72DF4","72DF5","72DF6","72DF7","72DF8","72DF9","72DFA","72DFB","72DFC","72DFD","72DFE","72DFF","72E00","72E01","72E02","72E03","72E04","72E05","72E06","72E07","72E08","72E09","72E0A","72E0B","72E0C","72E0D","72E0E","72E0F","72E10","72E11","72E12","72E13","72E14","72E15","72E16","72E17","72E18","72E19","72E1A","72E1B","72E1C","72E1D","72E1E","72E1F","72E20","72E21","72E22","72E23","72E24","72E25","72E26","72E27","72E28","72E29","72E2A","72E2B","72E2C","72E2D","72E2E","72E2F","72E30","72E31","72E32","72E33","72E34","72E35","72E36","72E37","72E38","72E39","72E3A","72E3B","72E3C","72E3D","72E3E","72E3F","72E40","72E41","72E42","72E43","72E44","72E45","72E46","72E47","72E48","72E49","72E4A","72E4B","72E4C","72E4D","72E4E","72E4F","72E50","72E51","72E52","72E53","72E54","72E55","72E56","72E57","72E58","72E59","72E5A","72E5B","72E5C","72E5D","72E5E","72E5F","72E60","72E61","72E62","72E63","72E64","72E65","72E66","72E67","72E68","72E69","72E6A","72E6B","72E6C","72E6D","72E6E","72E6F","72E70","72E71","72E72","72E73","72E74","72E75","72E76","72E77","72E78","72E79","72E7A","72E7B","72E7E","72E7F","72E85","72E86","72E87","72E88","72E8D","72E8E","72E8F","72E90","72E92","72E93","72E99","72EBB","72EBC","72EBD","72EBE","72EBF","72EC0","72EC1","72EC2","72EC4","72EC5","72EC6","72EC7","72EC8","72EC9","72ECA","72ECB","72ECC","72ECD","72ECE","72ED0","72ED1","72ED2","72ED3","72ED4","72ED5","72ED6","72ED7","72ED8","72ED9","72EDA","72F07","72F08","72F09","72F0A","72F0C"]},{"partId":"AC1001A--cad-region-004","sourceHandles":["73405","73406","73407"]},{"partId":"AC1001A--cad-region-005","sourceHandles":["71365","7166E","7167F","71926","71928","721E1","721E4","724C3","724CC","724CE","724D9","72513","7252D","7252E","7252F","72531","729A2","729A3","729A5","729A8","72C01","72C02","7302A","73042","73078","730A8","730FF","73101","73103","73105","73106","73107","73110","73112","73114","73115","732E7","73401","73404","73405","73406","73407"]},{"partId":"AC1001A--cad-region-006","sourceHandles":["732EB","732EC","732ED","732EE","732EF","732F0","732F1","732F2","73302","73305","73306","73307","73308","7330A","7330B","7330D","7330E","7330F","73310","73311","73312","73313","73322","73325","73326","73327","73328","73329","7332C","7332D","7332E","7332F","73332","73333","73334","73335","73337","73338","73339","7333E","7333F","73340","73341","73349","7334A","7334B","7334D","7334E","7334F","73350","73351","73352","73353","73354","73355","73356","73357","73359","7335A","7335B","7335D","73364","73365","73366","73367","73368","73369","7336A","7336B","7336C","7336D","7336E","7336F","73370","73372","73377","73378","7337C","7337D","7337E","73390","73398","73399","733A0","733A2","733A4","733A9","733AB","733AC","733AD","733B1","733B2","733B6","733B8","733B9","733BA","733C4","733CC","733D8","733DE","733DF","733E7","733E8","733E9","733F0","73403","734A4","734A5","734A7","734A8","734A9","734AA","734AB","734AC","734AD","734AE","734AF","734B0"]},{"partId":"AC1001A--cad-region-007","sourceHandles":["729DA","729DB","72A33","72A34","72A35","72A3C","72A45","72A46","72A47","72A48","72A49","72A4E","72A4F","72A50"]},{"partId":"AC1001A--cad-region-008","sourceHandles":["7101E","7101F","71020","71021","71022","710E1","710E2","712F6","712F7","712F8","73403"]},{"partId":"AC1001A--cad-region-009","sourceHandles":["72546","72549","725A4","725A5","725A7","72763","7276F","72777","72789","72794","727AC","727AE","727AF","727B0","727B1","727B2","733F4","733F5","733F6","733FB","733FC","733FD"]},{"partId":"AC1001A--cad-region-011","sourceHandles":["713B1","713E3","713E4","713F7","71621","71623","71670","71671","71676","7167C","7167D","7177D","7177E","71784","71785","72989","72994","72995","72998","7299A","7299E","729A0","729BE","729BF","729C1","729C3","72F34","72F35","72F38","73103","73104","73105","73108","7310A","732E7","73430"]},{"partId":"AC1001A--cad-region-012","sourceHandles":["71A33","73144","73147","73162","73163","73175"]},{"partId":"AC1001A--cad-region-013","sourceHandles":["7103B","7103F","71040","71041","71042","71045","71046","71050","71075","71076","7109E","710A0","710A4","710A5","710A6","710A7","710A8","710B1","710B2","710B3","710B4","710B5","710B6","710B7","710B8","710BA","710BB","710BC","710BD","710C1","710C4","710C5","710C6","710CC","710CE","710D3","710D7","710D8","710D9","710DB","710DD","710E4","710E5","710EB","710F0","710F3","710F8","710FC","710FE","7110F","71111","71116","71142","71276","71285","7129B","712A1","712A3","712A9","712AC","71302","71306","7130B","7130F"]},{"partId":"AC1001A--cad-region-014","sourceHandles":["71428","71618","7189D","7189E","718A2","718A4","718A7","71930","71931","7193B","7193D","72411","7241B","7241C","7241D","72420","72422","72423","72424","72513","729B9","729BB","729BC","72F28","72F2F","72F39","72F3E","72F40","72F54","72F5B","72F5F","72F60","72F63","72F69","72F70","72F73","72F75","72F78","72F79","72F7A","72F7D","72F80","72F84","72F86","72F88","72F89","72F8A","72F8B","72F8C","72F8D","72F8E","72F8F","72F90","72F92","72F9B","72F9D","72F9E","72FB1","72FB2","72FB6","72FB8","72FC0","72FC2","72FCB","72FCD","72FD6","72FD7","72FD8","72FD9","72FDA","72FDB","72FDC","72FDE","72FEC","72FED","72FEE","72FEF","72FF0","72FF1","72FF2","72FF3","72FF4","72FF5","72FF6","72FF7","72FFA","72FFB","72FFC","72FFE","72FFF","73000","73001","73004","73005","73008","73009","7300A","7300B","7300E","7300F","73010","73012","73013","73014","73015","73018","73019","7301C","7301D","7301E","7301F","73022","73023","73024","7302A","7302B","7302C","7302D","73030","73035","73036","7303A","7303C","7303D","7303E","7303F","73040","73041","73042","73047","73048","73049","7304B","7304C","73058","7305C","7305D","7305E","73062","73066","73067","73068","73069","7306A","7306C","7306D","7306F","73070","73071","73072","73073","73074","730A9","730AB","730AC","730AD","730AE","730AF","730B0","730B1","730B2","730B3","730B4","730B5","730B8","730BC","730BD","730BE","730BF","730C0","730C1","730C2","730C3","730C4","730C5","730C7","730C9","730CB","730CC","730CD","730CF","730D2","730D5","730D8","730D9","730DA","730DC","730DF","730E2","730E8","730EB","730EF","730F0","730F1","730F4","730F6","730F7","730F8","730FA","7310B","732E7"]},{"partId":"AC1001A--cad-region-015","sourceHandles":["71619","71674","71675","71679","7167A","71780","71781","718A0","718A5","718A9","718AC","7251F","72523","72524","72F34","72F36","72F37","72F38","72F3C","72F41","72F51","72F55","72F5C","72F61","72F65","72F68","72F6A","72F6F","72F72","72F74","72F7B","72F7C","72F7E","72F83","72F85","72F87","72F8B","72F98","72F99","72F9A","72FD3","72FD4","73027","73028","73029","7302A","7302E","7302F","73031","73037","7303C","7303D","7303F","73076","73077","73078","73079","7307A","7307B","7307C","7307D","7307E","73085","73086","73089","7308A","73091","73092","73094","73095","73096","7309A","7309B","7309C","7309E","7309F","730A0","730A2","730A5","730A6","730A7","730A8","730AA","730E6","730E7","730EC","730ED","730EE","730F2","730FC","732E7","73468","734A1"]},{"partId":"AC1001A--cad-region-017","sourceHandles":["7134C","71A0B","71A0C","71A0F","71A10","71A11","71A17","71A68","72D35","72D38"]},{"partId":"AC1001A--cad-region-018","sourceHandles":["7134C","72C0A","72D2E","72D32","72D34","72D35","72D36"]},{"partId":"AC1001A--cad-region-019","sourceHandles":["71A0C","71A0E","72D2E","72D34","72D35","72D38"]},{"partId":"AC1001A--cad-region-020","sourceHandles":["7134D","71625","71657","71658","71659","7165A","7165C","7165D","7165F","71684","71711","71712","71713","71714","7171D","7171E","7171F","71720","71721","71722","71723","71724","71725","71727","71728","71729","7172A","7172B","7172F","71731","71732","71733","7173D","7173E","7173F","71740","717D3","717FA","717FC","71907","71981","71A0F","71A13","71A3C"]},{"partId":"AC1001A--cad-region-024","sourceHandles":["7134F","71355","71DB1","72F08","72F0B","72F10","72F11"]},{"partId":"AC1001A--cad-region-025","sourceHandles":["71621","71642","7164D","71969","7196A","7196F","71974","71976","73116","73117","73118","73119","7311A","7311B","7311C","7311D","7311E","7311F","73120","73121","73122","73124","73125","73128","7312E","73138","73139","73181","73183","73186","7318B","73195","73197","73199","7319A","731A1","731A7","7340D","7340F","73419","7341B","73420","73422","7342C","7342E"]},{"partId":"AC1001A--cad-region-026","sourceHandles":["71A59","71DB1","71DB2","71DB5","72F0D","72F10","72F11"]},{"partId":"AC1001A--cad-region-027","sourceHandles":["71743","71744","71745","71746","71749","71753","71754","7175F","71760","717A8","717AB","717F4","7181D","7181E","71828","71829","7182F","71832","71833","718C5","718C9","719CA","719CC","71A2F","71A44","71DB9","73148","73153","73154","7344E"]},{"partId":"AC1001A--cad-region-028","sourceHandles":["717FF","71801","71803","71805","71A46","71A58","71A59","71BA6","71BA7","71DB1","71DB2","71DB4","71DB5","72EE3","72EE5","72EE6","72EEA","72EEB","72EEF","72EF0","72EF3","72EF4","72EF6","72F00","72F01","72F02","72F0D","72F0E","72F0F","72F11","73157","73158","73159","7315A","7315B","7315C","731BD","731C4","731C5","731C7","731CB","731CC","731CD","731D9","731DE","731DF","731E0","731E1","731E2","731E3","731E4","731E5","731E6","731EE","731EF","731F0","731F1","731F2","731F3","731F4","731F5","731F6","731F7","731F9","731FF","73200","73201","73202","73204","73205","73206","73207","7320B","7320D","7320E","7320F","73210","73212","7321C","7321D"]},{"partId":"AC1001A--cad-region-029","sourceHandles":["717F2","71A09","71A0B","71A11","71A3C","71A3F","71A40","71A41","71A42","71A43","71A5B","71DCB","71E9B","728D5","728E4","728E5","728F2","72D37","72D38","72D3F","72D40","72D41","72D42","72E80","72E81"]},{"partId":"AC1001A--cad-region-035","sourceHandles":["7134F","719FC","719FD","719FE","71A18","71A1A","71A45","71A46","71A4D","71A58","71A59","71DB1","72F11"]}] | AC1001A--cad-region-001
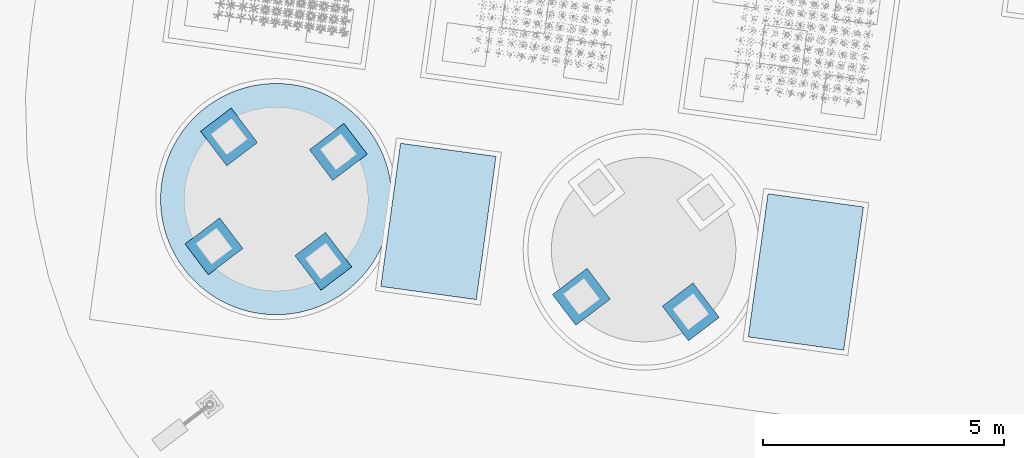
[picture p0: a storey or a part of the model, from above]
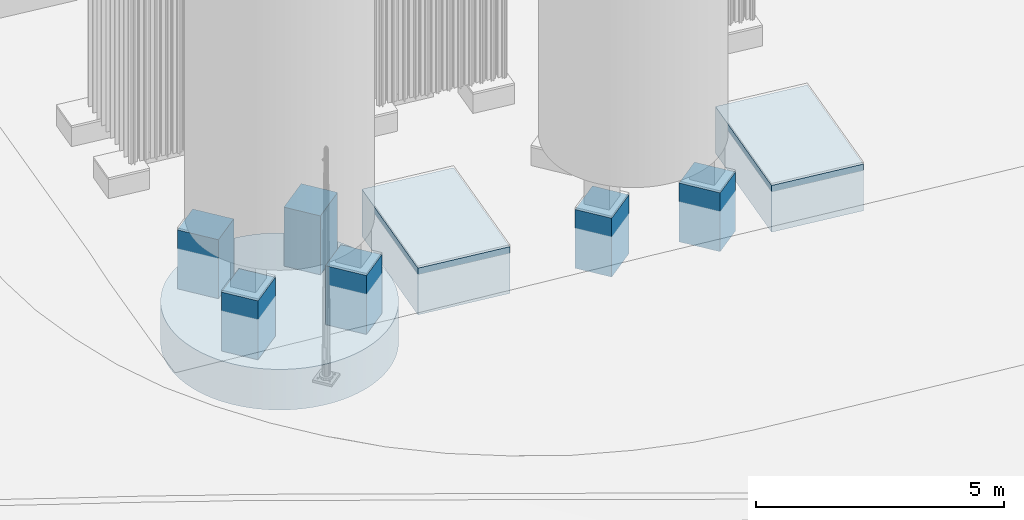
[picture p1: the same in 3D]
Properties of the parts of a building model (IFC4), part 60 of 134

# IfcCoolingTower: Envolvente de equipo (4)
JH_DetalleGeometrico - heightSource: {"documentId":"EQ-CARGAS-20260825","title":"Plano del fabricante: cargas de equipos","sheet":"Espacio modelo","date":"2026-08-25"}; revision: Detalle en planta de 2026-04-30 coordinado de forma preliminar con envolventes y alturas de 2026-08-25; horizontalStatus: derivado; verticalRule: Altura total documentada: 3,70 m. Distribución conceptual: cuerpo 0–3,20 m; plataforma superior 3,20–3,40 m; aro del ventilador 3,40–3,70 m; palas 3,52–3,56 m.; status: Submalla exacta; interpretación funcional y cotas parciales provisionales.; unconfirmedDimensions: ["Las cotas intermedias 3,20 / 3,40 / 3,52 / 3,56 m no aparecen acotadas en el fabricante.","Espesor de palas de 0,04 m y altura del aro de 0,30 m: hipótesis de visualización.","La sección y altura reales de la estructura y de los paneles permanecen sin confirmar."]; issues: ["El detalle de abril presenta una célula de 5,85 × 2,20 m; el contorno de agosto es de 5,85 × 2,14 m. Se usa el contorno de agosto. El ventilador se traslada al nuevo centro sin alterar su diámetro ni sus palas."]; material: No especificado; quantityUse: Magnitudes de la geometría representada; no son cantidades de material, obra, compra, capacidad útil ni fabricación. En geometrías compuestas se suman superficies y volúmenes de partes y pueden existir solapes no depurados.; partsAreBOM: no; sourceInsertHandle: 83619; partCount: 1; actualExtentManufacturerAxesM: [5.85,2.14,3.7]
JH_CapaBIM - IdentificadorCapa: equipment_enclosures; NombreCapa: Envolventes de equipos; Funcion: Componente de equipo · envolvente exterior; VisibilidadInicial: yes
JH_AcabadoVisual - Perfil: equipment_light_gray; Acabado: Equipo · gris claro provisional; ColorRGB: [0.88,0.89,0.88]; Rugosidad: 0.45; Metallicidad: 0.28; Estado: provisional; Referencia: Referencia visual de fotografías públicas de Jinhong Gas / fabricante. Apariencia provisional para coordinación; fotografías oficiales pueden orientar el color, pero no acreditan el material, el acabado ni el equipo concreto.; Nota: La apariencia no certifica el material físico ni el acabado de fabricación.
Name | dimensions | JH_InformacionBIM, source = Fuente del componente = DocumentoFuente = JH_DetalleGeometrico, source | positioning = PosicionYEstado | geometryMetrics | detailGeometry | parentEquipmentId = Identificador del fabricante o del modelo = Identificador del objeto = Identificador del elemento = Identificador del equipo padre = Identificador | parentEquipmentName = Equipo padre | parentEquipmentDimensions | assemblyBBox | assemblyGeometryMetrics | component | componentSeparation | assembly | visualizationIdentity | foundationRelationship | componentIds | childComponentIds | sourcePartIds | parentEquipmentProperties | Identificadores CAD del contorno (handles) | Referencia dimensional del conjunto | sourcePartHandles | sourcePartId | sourceHandles
Torre de refrigeración WT3001A · Envolvente del cuerpo de la torre | {"documented":[{"label":"Referencia dimensional del conjunto","value":"Plano general y dimensiones globales de WT3001A; no se asignan esas dimensiones globales a este componente.","unit":"","source":"EQ-CARGAS-20260825 · Espacio modelo","status":"referencia_del_conjunto"}],"geometry":[{"label":"Extensión de la malla en X","value":6.086959,"unit":"m","source":"Geometría releída del IFC; datum absoluto de proceso provisional","status":"derivado"},{"label":"Extensión de la malla en Y","value":2.9168500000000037,"unit":"m","source":"Geometría releída del IFC; datum absoluto de proceso provisional","status":"derivado"},{"label":"Extensión de la malla en Z","value":3.1999999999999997,"unit":"m","source":"Geometría releída del IFC; datum absoluto de proceso provisional","status":"derivado"},{"label":"Cota inferior de visualización","value":288.1,"unit":"m","source":"Geometría releída del IFC; datum absoluto de proceso provisional","status":"derivado"},{"label":"Cota superior de visualización","value":291.3,"unit":"m","source":"Geometría releída del IFC; datum absoluto de proceso provisional","status":"derivado"}],"notes":["Las dimensiones del equipo completo se conservan en parentEquipmentDimensions.","Las extensiones en X/Y son de los ejes del modelo y no sustituyen cotas locales de fabricación.","No se infieren espesores de chapa, tolerancias ni dimensiones de piezas a partir de la partición."]} | {"documentId":"EQ-CARGAS-20260825","title":"Plano del fabricante: cargas de equipos","sheet":"Espacio modelo","date":"2026-08-25","componentSourceHandles":["522","2659"]} | {"Estado de la planta":"Derivado del CAD y del giro de implantación","Nivel relativo del apoyo (m)":2.0,"Estado del nivel relativo":"Documentado en el plano de cimentaciones","Cero absoluto de visualización (m)":286.1,"Estado del cero absoluto":"Provisional","Cota del apoyo de visualización (m)":288.1,"Desplazamiento aplicado a la malla (m)":2.0000000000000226,"Criterio":"Nivel de apoyo relativo documentado. Se adopta el cero de proceso a 286,10 m solo para visualización; la equivalencia absoluta no está confirmada. No se añade un espesor de montaje sin cota del fabricante.","horizontalStatus":"derivado_del_conjunto","verticalStatus":"derivado_del_conjunto","coordinateSystem":"model_local_m","parentEquipmentId":"WT3001A","transformApplied":false,"note":"Coordenadas copiadas exactamente del equipo coordinado; no se ha movido, girado, elevado ni reescalado este componente.","foundationRelationship":"El apoyo y las cotas de instalación se documentan para el conjunto padre. Esta submalla no acredita un anclaje directo.","meshMinimumAbsoluteElevationM":288.1,"assemblyPlacementField":"parentEquipmentPositioning"} | {"boundingBoxM":{"min":[36.736357,48.464349,3.1],"max":[42.823316,51.381199,6.3]},"extentsM":[6.086959,2.91685,3.2],"meshSurfaceM2":76.174002,"meshVolumeM3":40.060801,"closedSolid":true,"basis":"Geometría de coordinación. Los volúmenes de referencia y subcomponentes no son cantidades de material ni componentes de fabricación certificados."} | {"source":{"documentId":"EQ-CARGAS-20260825","title":"Plano del fabricante: cargas de equipos","sheet":"Espacio modelo","date":"2026-08-25","componentSourceHandles":["522","2659"]},"heightSource":{"documentId":"EQ-CARGAS-20260825","title":"Plano del fabricante: cargas de equipos","sheet":"Espacio modelo","date":"2026-08-25"},"revision":"Detalle en planta de 2026-04-30 coordinado de forma preliminar con envolventes y alturas de 2026-08-25","horizontalStatus":"derivado","verticalRule":"Altura total documentada: 3,70 m. Distribución conceptual: cuerpo 0–3,20 m; plataforma superior 3,20–3,40 m; aro del ventilador 3,40–3,70 m; palas 3,52–3,56 m.","status":"Submalla exacta; interpretación funcional y cotas parciales provisionales.","unconfirmedDimensions":["Las cotas intermedias 3,20 / 3,40 / 3,52 / 3,56 m no aparecen acotadas en el fabricante.","Espesor de palas de 0,04 m y altura del aro de 0,30 m: hipótesis de visualización.","La sección y altura reales de la estructura y de los paneles permanecen sin confirmar."],"issues":["El detalle de abril presenta una célula de 5,85 × 2,20 m; el contorno de agosto es de 5,85 × 2,14 m. Se usa el contorno de agosto. El ventilador se traslada al nuevo centro sin alterar su diámetro ni sus palas."],"material":"No especificado","quantityUse":"Magnitudes de la geometría representada; no son cantidades de material, obra, compra, capacidad útil ni fabricación. En geometrías compuestas se suman superficies y volúmenes de partes y pueden existir solapes no depurados.","partsAreBOM":false,"sourceInsertHandle":"83619","partCount":1,"sourcePartHandles":[{"partId":"WT3001A--body","sourceHandles":["522","2659"]},{"partId":"WT3001A--top-frame","sourceHandles":["522","707EC"]},{"partId":"WT3001A--fan-ring","sourceHandles":["707EC","707ED"]},{"partId":"WT3001A--blade-01","sourceHandles":["70928"]},{"partId":"WT3001A--blade-02","sourceHandles":["7093F"]},{"partId":"WT3001A--blade-03","sourceHandles":["70956"]},{"partId":"WT3001A--blade-04","sourceHandles":["70970"]},{"partId":"WT3001A--blade-05","sourceHandles":["7098A"]},{"partId":"WT3001A--blade-06","sourceHandles":["709A0"]},{"partId":"WT3001A--fan-hub","sourceHandles":["709C2"]},{"partId":"WT3001A--lateral-mount-1","sourceHandles":["7080E"]},{"partId":"WT3001A--lateral-mount-2","sourceHandles":["7085E"]}],"actualExtentManufacturerAxesM":[5.85,2.14,3.7],"sourcePartId":"WT3001A--body","sourceHandles":["522","2659"]} | WT3001A | Torre de refrigeración WT3001A | {"documented":[{"label":"Dimensión X local del contorno CAD","value":5.85,"unit":"m","source":"EQ-CARGAS-20260825 · contorno CAD · handles 522","status":"derivado"},{"label":"Dimensión Y local del contorno CAD","value":2.14,"unit":"m","source":"EQ-CARGAS-20260825 · contorno CAD · handles 522","status":"derivado"},{"label":"Altura acotada","value":3.7,"unit":"m","source":"EQ-CARGAS-20260825 · handle 2659","status":"documentado"},{"label":"Cota relativa de la superficie de apoyo","value":2.0,"unit":"m","source":"LHD2609-JG00100-20260904 · sección 9 / 9-9 / 9A-9A · 2483D, 24841, 24772","status":"documentado"}],"geometry":[{"label":"Extensión de la malla en X","value":6.086959,"unit":"m","source":"Geometría releída del IFC; datum absoluto de proceso provisional","status":"derivado"},{"label":"Extensión de la malla en Y","value":2.9168500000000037,"unit":"m","source":"Geometría releída del IFC; datum absoluto de proceso provisional","status":"derivado"},{"label":"Extensión de la malla en Z","value":3.6999999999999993,"unit":"m","source":"Geometría releída del IFC; datum absoluto de proceso provisional","status":"derivado"},{"label":"Cota inferior de visualización","value":288.1,"unit":"m","source":"Geometría releída del IFC; datum absoluto de proceso provisional","status":"derivado"},{"label":"Cota superior de visualización","value":291.8,"unit":"m","source":"Geometría releída del IFC; datum absoluto de proceso provisional","status":"derivado"}],"notes":["Las extensiones de la malla se miden en los ejes del proyecto tras el giro de implantación; no sustituyen las dimensiones locales del fabricante.","La envolvente, su volumen y los espesores de visualización no son volúmenes de material ni cantidades de compra, construcción o fabricación.","Las dimensiones documentadas distinguen cotas explícitas y medidas extraídas de contornos CAD; las dimensiones geométricas describen únicamente la malla publicada.","Las extensiones de la malla refinada y las dimensiones documentadas del contorno o bastidor tienen distinto alcance; las cotas parciales del detalle son provisionales."]} | {"min":[36.736357,48.464349,3.1],"max":[42.823316,51.381199,6.8]} | {"boundingBoxM":{"min":[36.736357,48.464349,3.1],"max":[42.823316,51.381199,6.8]},"extentsM":[6.086959,2.9168500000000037,3.6999999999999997],"meshSurfaceM2":106.9519080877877,"meshVolumeM3":42.21444615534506,"closedSolid":true,"windingConsistent":true,"basis":"Submalla exacta de los triángulos del modelo IFC coordinado; separación de componentes sin transformación ni retesselación."} | {"id":"WT3001A","sourcePartId":"WT3001A--body","name":"Envolvente del cuerpo de la torre","role":"outer_body_envelope","classificationStatus":"provisional","classificationBasis":"Rol del subvolumen gráfico según el activo de detalle; identidad de fabricación no confirmada.","parentEquipmentId":"WT3001A","parentEquipmentGuid":"02xpqv6jnOLvupOblX$xct","isAssemblyIdentityCarrier":true,"sourceFaceRange":[0,12],"sourceCurrentFaceIndices":[0,1,2,3,4,5,6,7,8,9,10,11],"sourceMeshSha256":"7b60c904c9d84d22fded9be34af09a09a9c198ec8e75e61902634d5e4064c761","sourceVertexIndices":[0,1,2,3,4,5,6,7],"separationMethod":"Partición exacta de triángulos existentes; coordenadas y orientación de caras conservadas.","quantityUse":"Magnitudes geométricas del subvolumen; no son cantidades netas de material, fabricación, suministro o capacidad."} | {"status":"componente_independiente","note":"Objeto independiente seleccionable. Las caras se asignan una sola vez entre todos los componentes del conjunto.","parentEquipmentId":"WT3001A","isAssemblyIdentityCarrier":true} | {"id":"WT3001A","name":"Torre de refrigeración WT3001A","relationship":"identity_carrier_with_child_components","parentShapeMeaning":"La forma del objeto que conserva el ID del equipo es únicamente su componente principal; el conjunto completo requiere sus hijos."} | {"elementId":"WT3001A","ifcGuid":"02xpqv6jnOLvupOblX$xct","ifcClass":"IfcCoolingTower","buildingId":"process_plant","buildingName":"Planta de proceso","sourceDocumentId":"EQ-CARGAS-20260825","sourceRepresentationKind":"equipmentComponent"} | {"kind":"assembly_documentation","parentEquipmentId":"WT3001A","directAnchorageVerified":false,"note":"La relación del conjunto con cimentaciones se conserva en el objeto que mantiene el ID del equipo; no se atribuye fijación directa a cada subcomponente."} | ["WT3001A","WT3001A--top-frame","WT3001A--fan-ring","WT3001A--blade-01","WT3001A--blade-02","WT3001A--blade-03","WT3001A--blade-04","WT3001A--blade-05","WT3001A--blade-06","WT3001A--fan-hub","WT3001A--lateral-mount-1","WT3001A--lateral-mount-2"] | ["WT3001A--top-frame","WT3001A--fan-ring","WT3001A--blade-01","WT3001A--blade-02","WT3001A--blade-03","WT3001A--blade-04","WT3001A--blade-05","WT3001A--blade-06","WT3001A--fan-hub","WT3001A--lateral-mount-1","WT3001A--lateral-mount-2"] | ["WT3001A--body","WT3001A--top-frame","WT3001A--fan-ring","WT3001A--blade-01","WT3001A--blade-02","WT3001A--blade-03","WT3001A--blade-04","WT3001A--blade-05","WT3001A--blade-06","WT3001A--fan-hub","WT3001A--lateral-mount-1","WT3001A--lateral-mount-2"] | {"Referencia en el plano del fabricante":"9","Identificador del fabricante o del modelo":"WT3001A","Documento de origen":"Plano del fabricante: cargas de equipos · 2026-08-25 · Espacio modelo; número de plano no identificado","Documento CAD derivado":"Conversión DXF del plano de cargas de equipos · 2026-08-25 · espacio modelo","Capa CAD de referencia":"Anotaciones y contornos de equipos","Identificadores CAD del contorno (handles)":"522","Identificador CAD de la cota de altura (handle)":"2659","Cota de altura del fabricante (traducción)":"Altura del equipo: 3.7m","Altura (m)":3.7,"Origen de las dimensiones":"Plano de cargas del fabricante de 2026-08-25: lectura directa del contorno CAD cerrado y de la cota de altura del equipo.","Grado de definición":"Planta derivada del CAD, altura total documentada y alturas parciales provisionales.","Alcance de la geometría":"Geometría compuesta con perfiles CAD y distribución vertical provisional; véase Detalle geométrico.","Origen de la posición":"Punto de referencia del fabricante: entidad CIRCLE, handle 98, en la esquina inferior izquierda de la zona de equipos. Los ejes X e Y son locales y se giran para su implantación UTM.","Hipótesis de modelado":"Nivel de apoyo relativo documentado. Se adopta el cero de proceso a 286,10 m solo para visualización; la equivalencia absoluta no está confirmada. No se añade un espesor de montaje sin cota del fabricante.","Observaciones":"Cuatro unidades adyacentes. El contorno duplicado 523, coincidente con 522, se eliminó. Masa permanente total indicada: 23 000 kg; 5 750 kg por unidad es un reparto aritmético uniforme. La altura corresponde a la envolvente del cuerpo; barandillas y sombreretes de ventiladores no se modelan por separado.","Masa propia indicada (kg)":5750,"Dimensión X local (m)":5.85,"Dimensión Y local (m)":2.14,"Dimensiones de la plataforma de equipos (m)":"27 × 57 m; dimensiones acotadas en el plano general.","Implantación de la plataforma de equipos":"El punto de referencia del fabricante coincide con la esquina suroeste de la zona de equipos. Giro local de −7,82824° para la implantación en coordenadas UTM.","Estado de la cota de instalación":"Nivel de apoyo relativo documentado. Se adopta el cero de proceso a 286,10 m solo para visualización; la equivalencia absoluta no está confirmada. No se añade un espesor de montaje sin cota del fabricante.","Convención de coordenadas":"Coordenadas locales del proyecto en metros. Añadir (729400, 4301550, 285) para recuperar las coordenadas UTM y las cotas del plano.","Identificador del objeto":"WT3001A","Disciplina":"Equipos","Clase IFC":"IfcCoolingTower","Fase del modelo":"Revisión de la zona de separación de aire · septiembre de 2026","Representación geométrica IFC":"Sólido IFC4 mediante malla triangular cerrada","Aplicabilidad a mediciones":"Magnitudes de la geometría representada; no son cantidades de material, obra, compra, capacidad útil ni fabricación. En geometrías compuestas se suman superficies y volúmenes de partes y pueden existir solapes no depurados.","Origen de la masa por unidad":"5 750 kg = 23 000 kg / 4; reparto uniforme derivado, pendiente de confirmar por el fabricante.","Material":"No especificado","Estado de la información":"provisional","Detalle geométrico":"derivado","Incidencias del detalle":["Nivel de apoyo relativo documentado. Se adopta el cero de proceso a 286,10 m solo para visualización; la equivalencia absoluta no está confirmada. No se añade un espesor de montaje sin cota del fabricante.","La masa de 5 750 kg por unidad es el reparto uniforme de 23 000 kg del conjunto; confirmar el reparto real de cargas. Barandillas y sombreretes no se detallan.","El detalle de abril presenta una célula de 5,85 × 2,20 m; el contorno de agosto es de 5,85 × 2,14 m. Se usa el contorno de agosto. El ventilador se traslada al nuevo centro sin alterar su diámetro ni sus palas.","Las cotas intermedias 3,20 / 3,40 / 3,52 / 3,56 m no aparecen acotadas en el fabricante.","Espesor de palas de 0,04 m y altura del aro de 0,30 m: hipótesis de visualización.","La sección y altura reales de la estructura y de los paneles permanecen sin confirmar."],"Extensión X del conjunto refinado en ejes del fabricante (m)":5.85,"Extensión Y del conjunto refinado en ejes del fabricante (m)":2.1400000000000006,"Nivel relativo de apoyo documentado (m)":2.0,"Fuente del nivel de apoyo":{"documentId":"LHD2609-JG00100-20260904","title":"Cimentaciones y pedestales de equipos · revisión recibida 04/09/2026","date":"2026-09-04","sheet":"9 / 9-9 / 9A-9A","sourceHandles":["2483D","24841","24772"]},"Criterio de instalación":"Nivel de apoyo relativo documentado. Se adopta el cero de proceso a 286,10 m solo para visualización; la equivalencia absoluta no está confirmada. No se añade un espesor de montaje sin cota del fabricante."} | 522 | Plano general y dimensiones globales de WT3001A; no se asignan esas dimensiones globales a este componente. | [{"partId":"WT3001A--body","sourceHandles":["522","2659"]},{"partId":"WT3001A--top-frame","sourceHandles":["522","707EC"]},{"partId":"WT3001A--fan-ring","sourceHandles":["707EC","707ED"]},{"partId":"WT3001A--blade-01","sourceHandles":["70928"]},{"partId":"WT3001A--blade-02","sourceHandles":["7093F"]},{"partId":"WT3001A--blade-03","sourceHandles":["70956"]},{"partId":"WT3001A--blade-04","sourceHandles":["70970"]},{"partId":"WT3001A--blade-05","sourceHandles":["7098A"]},{"partId":"WT3001A--blade-06","sourceHandles":["709A0"]},{"partId":"WT3001A--fan-hub","sourceHandles":["709C2"]},{"partId":"WT3001A--lateral-mount-1","sourceHandles":["7080E"]},{"partId":"WT3001A--lateral-mount-2","sourceHandles":["7085E"]}] | WT3001A--body | ["522","2659"]
Torre de refrigeración WT3001B · Envolvente del cuerpo de la torre | {"documented":[{"label":"Referencia dimensional del conjunto","value":"Plano general y dimensiones globales de WT3001B; no se asignan esas dimensiones globales a este componente.","unit":"","source":"EQ-CARGAS-20260825 · Espacio modelo","status":"referencia_del_conjunto"}],"geometry":[{"label":"Extensión de la malla en X","value":6.086960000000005,"unit":"m","source":"Geometría releída del IFC; datum absoluto de proceso provisional","status":"derivado"},{"label":"Extensión de la malla en Y","value":2.9168499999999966,"unit":"m","source":"Geometría releída del IFC; datum absoluto de proceso provisional","status":"derivado"},{"label":"Extensión de la malla en Z","value":3.1999999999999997,"unit":"m","source":"Geometría releída del IFC; datum absoluto de proceso provisional","status":"derivado"},{"label":"Cota inferior de visualización","value":288.1,"unit":"m","source":"Geometría releída del IFC; datum absoluto de proceso provisional","status":"derivado"},{"label":"Cota superior de visualización","value":291.3,"unit":"m","source":"Geometría releída del IFC; datum absoluto de proceso provisional","status":"derivado"}],"notes":["Las dimensiones del equipo completo se conservan en parentEquipmentDimensions.","Las extensiones en X/Y son de los ejes del modelo y no sustituyen cotas locales de fabricación.","No se infieren espesores de chapa, tolerancias ni dimensiones de piezas a partir de la partición."]} | {"documentId":"EQ-CARGAS-20260825","title":"Plano del fabricante: cargas de equipos","sheet":"Espacio modelo","date":"2026-08-25","componentSourceHandles":["524","2659"]} | {"Estado de la planta":"Derivado del CAD y del giro de implantación","Nivel relativo del apoyo (m)":2.0,"Estado del nivel relativo":"Documentado en el plano de cimentaciones","Cero absoluto de visualización (m)":286.1,"Estado del cero absoluto":"Provisional","Cota del apoyo de visualización (m)":288.1,"Desplazamiento aplicado a la malla (m)":2.0000000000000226,"Criterio":"Nivel de apoyo relativo documentado. Se adopta el cero de proceso a 286,10 m solo para visualización; la equivalencia absoluta no está confirmada. No se añade un espesor de montaje sin cota del fabricante.","horizontalStatus":"derivado_del_conjunto","verticalStatus":"derivado_del_conjunto","coordinateSystem":"model_local_m","parentEquipmentId":"WT3001B","transformApplied":false,"note":"Coordenadas copiadas exactamente del equipo coordinado; no se ha movido, girado, elevado ni reescalado este componente.","foundationRelationship":"El apoyo y las cotas de instalación se documentan para el conjunto padre. Esta submalla no acredita un anclaje directo.","meshMinimumAbsoluteElevationM":288.1,"assemblyPlacementField":"parentEquipmentPositioning"} | {"boundingBoxM":{"min":[36.44488,46.344292,3.1],"max":[42.53184,49.261142,6.3]},"extentsM":[6.08696,2.91685,3.2],"meshSurfaceM2":76.174004,"meshVolumeM3":40.060804,"closedSolid":true,"basis":"Geometría de coordinación. Los volúmenes de referencia y subcomponentes no son cantidades de material ni componentes de fabricación certificados."} | {"source":{"documentId":"EQ-CARGAS-20260825","title":"Plano del fabricante: cargas de equipos","sheet":"Espacio modelo","date":"2026-08-25","componentSourceHandles":["524","2659"]},"heightSource":{"documentId":"EQ-CARGAS-20260825","title":"Plano del fabricante: cargas de equipos","sheet":"Espacio modelo","date":"2026-08-25"},"revision":"Detalle en planta de 2026-04-30 coordinado de forma preliminar con envolventes y alturas de 2026-08-25","horizontalStatus":"derivado","verticalRule":"Altura total documentada: 3,70 m. Distribución conceptual: cuerpo 0–3,20 m; plataforma superior 3,20–3,40 m; aro del ventilador 3,40–3,70 m; palas 3,52–3,56 m.","status":"Submalla exacta; interpretación funcional y cotas parciales provisionales.","unconfirmedDimensions":["Las cotas intermedias 3,20 / 3,40 / 3,52 / 3,56 m no aparecen acotadas en el fabricante.","Espesor de palas de 0,04 m y altura del aro de 0,30 m: hipótesis de visualización.","La sección y altura reales de la estructura y de los paneles permanecen sin confirmar."],"issues":["El detalle de abril presenta una célula de 5,85 × 2,20 m; el contorno de agosto es de 5,85 × 2,14 m. Se usa el contorno de agosto. El ventilador se traslada al nuevo centro sin alterar su diámetro ni sus palas."],"material":"No especificado","quantityUse":"Magnitudes de la geometría representada; no son cantidades de material, obra, compra, capacidad útil ni fabricación. En geometrías compuestas se suman superficies y volúmenes de partes y pueden existir solapes no depurados.","partsAreBOM":false,"sourceInsertHandle":"83619","partCount":1,"sourcePartHandles":[{"partId":"WT3001B--body","sourceHandles":["524","2659"]},{"partId":"WT3001B--top-frame","sourceHandles":["524","707EC"]},{"partId":"WT3001B--fan-ring","sourceHandles":["707EC","707ED"]},{"partId":"WT3001B--blade-01","sourceHandles":["70928"]},{"partId":"WT3001B--blade-02","sourceHandles":["7093F"]},{"partId":"WT3001B--blade-03","sourceHandles":["70956"]},{"partId":"WT3001B--blade-04","sourceHandles":["70970"]},{"partId":"WT3001B--blade-05","sourceHandles":["7098A"]},{"partId":"WT3001B--blade-06","sourceHandles":["709A0"]},{"partId":"WT3001B--fan-hub","sourceHandles":["709C2"]},{"partId":"WT3001B--lateral-mount-1","sourceHandles":["7080E"]},{"partId":"WT3001B--lateral-mount-2","sourceHandles":["7085E"]}],"actualExtentManufacturerAxesM":[5.85,2.14,3.7],"sourcePartId":"WT3001B--body","sourceHandles":["524","2659"]} | WT3001B | Torre de refrigeración WT3001B | {"documented":[{"label":"Dimensión X local del contorno CAD","value":5.85,"unit":"m","source":"EQ-CARGAS-20260825 · contorno CAD · handles 524","status":"derivado"},{"label":"Dimensión Y local del contorno CAD","value":2.14,"unit":"m","source":"EQ-CARGAS-20260825 · contorno CAD · handles 524","status":"derivado"},{"label":"Altura acotada","value":3.7,"unit":"m","source":"EQ-CARGAS-20260825 · handle 2659","status":"documentado"},{"label":"Cota relativa de la superficie de apoyo","value":2.0,"unit":"m","source":"LHD2609-JG00100-20260904 · sección 9 / 9-9 / 9A-9A · 2483D, 24841, 24772","status":"documentado"}],"geometry":[{"label":"Extensión de la malla en X","value":6.086960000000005,"unit":"m","source":"Geometría releída del IFC; datum absoluto de proceso provisional","status":"derivado"},{"label":"Extensión de la malla en Y","value":2.9168499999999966,"unit":"m","source":"Geometría releída del IFC; datum absoluto de proceso provisional","status":"derivado"},{"label":"Extensión de la malla en Z","value":3.6999999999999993,"unit":"m","source":"Geometría releída del IFC; datum absoluto de proceso provisional","status":"derivado"},{"label":"Cota inferior de visualización","value":288.1,"unit":"m","source":"Geometría releída del IFC; datum absoluto de proceso provisional","status":"derivado"},{"label":"Cota superior de visualización","value":291.8,"unit":"m","source":"Geometría releída del IFC; datum absoluto de proceso provisional","status":"derivado"}],"notes":["Las extensiones de la malla se miden en los ejes del proyecto tras el giro de implantación; no sustituyen las dimensiones locales del fabricante.","La envolvente, su volumen y los espesores de visualización no son volúmenes de material ni cantidades de compra, construcción o fabricación.","Las dimensiones documentadas distinguen cotas explícitas y medidas extraídas de contornos CAD; las dimensiones geométricas describen únicamente la malla publicada.","Las extensiones de la malla refinada y las dimensiones documentadas del contorno o bastidor tienen distinto alcance; las cotas parciales del detalle son provisionales."]} | {"min":[36.44488,46.344292,3.1],"max":[42.53184,49.261142,6.8]} | {"boundingBoxM":{"min":[36.44488,46.344292,3.1],"max":[42.53184,49.261142,6.8]},"extentsM":[6.086960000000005,2.9168499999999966,3.6999999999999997],"meshSurfaceM2":106.9519119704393,"meshVolumeM3":42.21444876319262,"closedSolid":true,"windingConsistent":true,"basis":"Submalla exacta de los triángulos del modelo IFC coordinado; separación de componentes sin transformación ni retesselación."} | {"id":"WT3001B","sourcePartId":"WT3001B--body","name":"Envolvente del cuerpo de la torre","role":"outer_body_envelope","classificationStatus":"provisional","classificationBasis":"Rol del subvolumen gráfico según el activo de detalle; identidad de fabricación no confirmada.","parentEquipmentId":"WT3001B","parentEquipmentGuid":"3QfAgBB2zPsvSc6AB8$nne","isAssemblyIdentityCarrier":true,"sourceFaceRange":[0,12],"sourceCurrentFaceIndices":[0,1,2,3,4,5,6,7,8,9,10,11],"sourceMeshSha256":"7b60c904c9d84d22fded9be34af09a09a9c198ec8e75e61902634d5e4064c761","sourceVertexIndices":[0,1,2,3,4,5,6,7],"separationMethod":"Partición exacta de triángulos existentes; coordenadas y orientación de caras conservadas.","quantityUse":"Magnitudes geométricas del subvolumen; no son cantidades netas de material, fabricación, suministro o capacidad."} | {"status":"componente_independiente","note":"Objeto independiente seleccionable. Las caras se asignan una sola vez entre todos los componentes del conjunto.","parentEquipmentId":"WT3001B","isAssemblyIdentityCarrier":true} | {"id":"WT3001B","name":"Torre de refrigeración WT3001B","relationship":"identity_carrier_with_child_components","parentShapeMeaning":"La forma del objeto que conserva el ID del equipo es únicamente su componente principal; el conjunto completo requiere sus hijos."} | {"elementId":"WT3001B","ifcGuid":"3QfAgBB2zPsvSc6AB8$nne","ifcClass":"IfcCoolingTower","buildingId":"process_plant","buildingName":"Planta de proceso","sourceDocumentId":"EQ-CARGAS-20260825","sourceRepresentationKind":"equipmentComponent"} | {"kind":"assembly_documentation","parentEquipmentId":"WT3001B","directAnchorageVerified":false,"note":"La relación del conjunto con cimentaciones se conserva en el objeto que mantiene el ID del equipo; no se atribuye fijación directa a cada subcomponente."} | ["WT3001B","WT3001B--top-frame","WT3001B--fan-ring","WT3001B--blade-01","WT3001B--blade-02","WT3001B--blade-03","WT3001B--blade-04","WT3001B--blade-05","WT3001B--blade-06","WT3001B--fan-hub","WT3001B--lateral-mount-1","WT3001B--lateral-mount-2"] | ["WT3001B--top-frame","WT3001B--fan-ring","WT3001B--blade-01","WT3001B--blade-02","WT3001B--blade-03","WT3001B--blade-04","WT3001B--blade-05","WT3001B--blade-06","WT3001B--fan-hub","WT3001B--lateral-mount-1","WT3001B--lateral-mount-2"] | ["WT3001B--body","WT3001B--top-frame","WT3001B--fan-ring","WT3001B--blade-01","WT3001B--blade-02","WT3001B--blade-03","WT3001B--blade-04","WT3001B--blade-05","WT3001B--blade-06","WT3001B--fan-hub","WT3001B--lateral-mount-1","WT3001B--lateral-mount-2"] | {"Referencia en el plano del fabricante":"9","Identificador del fabricante o del modelo":"WT3001B","Documento de origen":"Plano del fabricante: cargas de equipos · 2026-08-25 · Espacio modelo; número de plano no identificado","Documento CAD derivado":"Conversión DXF del plano de cargas de equipos · 2026-08-25 · espacio modelo","Capa CAD de referencia":"Anotaciones y contornos de equipos","Identificadores CAD del contorno (handles)":"524","Identificador CAD de la cota de altura (handle)":"2659","Cota de altura del fabricante (traducción)":"Altura del equipo: 3.7m","Altura (m)":3.7,"Origen de las dimensiones":"Plano de cargas del fabricante de 2026-08-25: lectura directa del contorno CAD cerrado y de la cota de altura del equipo.","Grado de definición":"Planta derivada del CAD, altura total documentada y alturas parciales provisionales.","Alcance de la geometría":"Geometría compuesta con perfiles CAD y distribución vertical provisional; véase Detalle geométrico.","Origen de la posición":"Punto de referencia del fabricante: entidad CIRCLE, handle 98, en la esquina inferior izquierda de la zona de equipos. Los ejes X e Y son locales y se giran para su implantación UTM.","Hipótesis de modelado":"Nivel de apoyo relativo documentado. Se adopta el cero de proceso a 286,10 m solo para visualización; la equivalencia absoluta no está confirmada. No se añade un espesor de montaje sin cota del fabricante.","Observaciones":"Cuatro unidades adyacentes. El contorno duplicado 523, coincidente con 522, se eliminó. Masa permanente total indicada: 23 000 kg; 5 750 kg por unidad es un reparto aritmético uniforme. La altura corresponde a la envolvente del cuerpo; barandillas y sombreretes de ventiladores no se modelan por separado.","Masa propia indicada (kg)":5750,"Dimensión X local (m)":5.85,"Dimensión Y local (m)":2.14,"Dimensiones de la plataforma de equipos (m)":"27 × 57 m; dimensiones acotadas en el plano general.","Implantación de la plataforma de equipos":"El punto de referencia del fabricante coincide con la esquina suroeste de la zona de equipos. Giro local de −7,82824° para la implantación en coordenadas UTM.","Estado de la cota de instalación":"Nivel de apoyo relativo documentado. Se adopta el cero de proceso a 286,10 m solo para visualización; la equivalencia absoluta no está confirmada. No se añade un espesor de montaje sin cota del fabricante.","Convención de coordenadas":"Coordenadas locales del proyecto en metros. Añadir (729400, 4301550, 285) para recuperar las coordenadas UTM y las cotas del plano.","Identificador del objeto":"WT3001B","Disciplina":"Equipos","Clase IFC":"IfcCoolingTower","Fase del modelo":"Revisión de la zona de separación de aire · septiembre de 2026","Representación geométrica IFC":"Sólido IFC4 mediante malla triangular cerrada","Aplicabilidad a mediciones":"Magnitudes de la geometría representada; no son cantidades de material, obra, compra, capacidad útil ni fabricación. En geometrías compuestas se suman superficies y volúmenes de partes y pueden existir solapes no depurados.","Origen de la masa por unidad":"5 750 kg = 23 000 kg / 4; reparto uniforme derivado, pendiente de confirmar por el fabricante.","Material":"No especificado","Estado de la información":"provisional","Detalle geométrico":"derivado","Incidencias del detalle":["Nivel de apoyo relativo documentado. Se adopta el cero de proceso a 286,10 m solo para visualización; la equivalencia absoluta no está confirmada. No se añade un espesor de montaje sin cota del fabricante.","La masa de 5 750 kg por unidad es el reparto uniforme de 23 000 kg del conjunto; confirmar el reparto real de cargas. Barandillas y sombreretes no se detallan.","El detalle de abril presenta una célula de 5,85 × 2,20 m; el contorno de agosto es de 5,85 × 2,14 m. Se usa el contorno de agosto. El ventilador se traslada al nuevo centro sin alterar su diámetro ni sus palas.","Las cotas intermedias 3,20 / 3,40 / 3,52 / 3,56 m no aparecen acotadas en el fabricante.","Espesor de palas de 0,04 m y altura del aro de 0,30 m: hipótesis de visualización.","La sección y altura reales de la estructura y de los paneles permanecen sin confirmar."],"Extensión X del conjunto refinado en ejes del fabricante (m)":5.85,"Extensión Y del conjunto refinado en ejes del fabricante (m)":2.1400000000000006,"Nivel relativo de apoyo documentado (m)":2.0,"Fuente del nivel de apoyo":{"documentId":"LHD2609-JG00100-20260904","title":"Cimentaciones y pedestales de equipos · revisión recibida 04/09/2026","date":"2026-09-04","sheet":"9 / 9-9 / 9A-9A","sourceHandles":["2483D","24841","24772"]},"Criterio de instalación":"Nivel de apoyo relativo documentado. Se adopta el cero de proceso a 286,10 m solo para visualización; la equivalencia absoluta no está confirmada. No se añade un espesor de montaje sin cota del fabricante."} | 524 | Plano general y dimensiones globales de WT3001B; no se asignan esas dimensiones globales a este componente. | [{"partId":"WT3001B--body","sourceHandles":["524","2659"]},{"partId":"WT3001B--top-frame","sourceHandles":["524","707EC"]},{"partId":"WT3001B--fan-ring","sourceHandles":["707EC","707ED"]},{"partId":"WT3001B--blade-01","sourceHandles":["70928"]},{"partId":"WT3001B--blade-02","sourceHandles":["7093F"]},{"partId":"WT3001B--blade-03","sourceHandles":["70956"]},{"partId":"WT3001B--blade-04","sourceHandles":["70970"]},{"partId":"WT3001B--blade-05","sourceHandles":["7098A"]},{"partId":"WT3001B--blade-06","sourceHandles":["709A0"]},{"partId":"WT3001B--fan-hub","sourceHandles":["709C2"]},{"partId":"WT3001B--lateral-mount-1","sourceHandles":["7080E"]},{"partId":"WT3001B--lateral-mount-2","sourceHandles":["7085E"]}] | WT3001B--body | ["524","2659"]
Torre de refrigeración WT3001C · Envolvente del cuerpo de la torre | {"documented":[{"label":"Referencia dimensional del conjunto","value":"Plano general y dimensiones globales de WT3001C; no se asignan esas dimensiones globales a este componente.","unit":"","source":"EQ-CARGAS-20260825 · Espacio modelo","status":"referencia_del_conjunto"}],"geometry":[{"label":"Extensión de la malla en X","value":6.086959,"unit":"m","source":"Geometría releída del IFC; datum absoluto de proceso provisional","status":"derivado"},{"label":"Extensión de la malla en Y","value":2.9168499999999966,"unit":"m","source":"Geometría releída del IFC; datum absoluto de proceso provisional","status":"derivado"},{"label":"Extensión de la malla en Z","value":3.1999999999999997,"unit":"m","source":"Geometría releída del IFC; datum absoluto de proceso provisional","status":"derivado"},{"label":"Cota inferior de visualización","value":288.1,"unit":"m","source":"Geometría releída del IFC; datum absoluto de proceso provisional","status":"derivado"},{"label":"Cota superior de visualización","value":291.3,"unit":"m","source":"Geometría releída del IFC; datum absoluto de proceso provisional","status":"derivado"}],"notes":["Las dimensiones del equipo completo se conservan en parentEquipmentDimensions.","Las extensiones en X/Y son de los ejes del modelo y no sustituyen cotas locales de fabricación.","No se infieren espesores de chapa, tolerancias ni dimensiones de piezas a partir de la partición."]} | {"documentId":"EQ-CARGAS-20260825","title":"Plano del fabricante: cargas de equipos","sheet":"Espacio modelo","date":"2026-08-25","componentSourceHandles":["525","2659"]} | {"Estado de la planta":"Derivado del CAD y del giro de implantación","Nivel relativo del apoyo (m)":2.0,"Estado del nivel relativo":"Documentado en el plano de cimentaciones","Cero absoluto de visualización (m)":286.1,"Estado del cero absoluto":"Provisional","Cota del apoyo de visualización (m)":288.1,"Desplazamiento aplicado a la malla (m)":2.0000000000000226,"Criterio":"Nivel de apoyo relativo documentado. Se adopta el cero de proceso a 286,10 m solo para visualización; la equivalencia absoluta no está confirmada. No se añade un espesor de montaje sin cota del fabricante.","horizontalStatus":"derivado_del_conjunto","verticalStatus":"derivado_del_conjunto","coordinateSystem":"model_local_m","parentEquipmentId":"WT3001C","transformApplied":false,"note":"Coordenadas copiadas exactamente del equipo coordinado; no se ha movido, girado, elevado ni reescalado este componente.","foundationRelationship":"El apoyo y las cotas de instalación se documentan para el conjunto padre. Esta submalla no acredita un anclaje directo.","meshMinimumAbsoluteElevationM":288.1,"assemblyPlacementField":"parentEquipmentPositioning"} | {"boundingBoxM":{"min":[36.153404,44.224235,3.1],"max":[42.240363,47.141085,6.3]},"extentsM":[6.086959,2.91685,3.2],"meshSurfaceM2":76.174002,"meshVolumeM3":40.060801,"closedSolid":true,"basis":"Geometría de coordinación. Los volúmenes de referencia y subcomponentes no son cantidades de material ni componentes de fabricación certificados."} | {"source":{"documentId":"EQ-CARGAS-20260825","title":"Plano del fabricante: cargas de equipos","sheet":"Espacio modelo","date":"2026-08-25","componentSourceHandles":["525","2659"]},"heightSource":{"documentId":"EQ-CARGAS-20260825","title":"Plano del fabricante: cargas de equipos","sheet":"Espacio modelo","date":"2026-08-25"},"revision":"Detalle en planta de 2026-04-30 coordinado de forma preliminar con envolventes y alturas de 2026-08-25","horizontalStatus":"derivado","verticalRule":"Altura total documentada: 3,70 m. Distribución conceptual: cuerpo 0–3,20 m; plataforma superior 3,20–3,40 m; aro del ventilador 3,40–3,70 m; palas 3,52–3,56 m.","status":"Submalla exacta; interpretación funcional y cotas parciales provisionales.","unconfirmedDimensions":["Las cotas intermedias 3,20 / 3,40 / 3,52 / 3,56 m no aparecen acotadas en el fabricante.","Espesor de palas de 0,04 m y altura del aro de 0,30 m: hipótesis de visualización.","La sección y altura reales de la estructura y de los paneles permanecen sin confirmar."],"issues":["El detalle de abril presenta una célula de 5,85 × 2,20 m; el contorno de agosto es de 5,85 × 2,14 m. Se usa el contorno de agosto. El ventilador se traslada al nuevo centro sin alterar su diámetro ni sus palas."],"material":"No especificado","quantityUse":"Magnitudes de la geometría representada; no son cantidades de material, obra, compra, capacidad útil ni fabricación. En geometrías compuestas se suman superficies y volúmenes de partes y pueden existir solapes no depurados.","partsAreBOM":false,"sourceInsertHandle":"83619","partCount":1,"sourcePartHandles":[{"partId":"WT3001C--body","sourceHandles":["525","2659"]},{"partId":"WT3001C--top-frame","sourceHandles":["525","707EC"]},{"partId":"WT3001C--fan-ring","sourceHandles":["707EC","707ED"]},{"partId":"WT3001C--blade-01","sourceHandles":["70928"]},{"partId":"WT3001C--blade-02","sourceHandles":["7093F"]},{"partId":"WT3001C--blade-03","sourceHandles":["70956"]},{"partId":"WT3001C--blade-04","sourceHandles":["70970"]},{"partId":"WT3001C--blade-05","sourceHandles":["7098A"]},{"partId":"WT3001C--blade-06","sourceHandles":["709A0"]},{"partId":"WT3001C--fan-hub","sourceHandles":["709C2"]},{"partId":"WT3001C--lateral-mount-1","sourceHandles":["7080E"]},{"partId":"WT3001C--lateral-mount-2","sourceHandles":["7085E"]}],"actualExtentManufacturerAxesM":[5.85,2.14,3.7],"sourcePartId":"WT3001C--body","sourceHandles":["525","2659"]} | WT3001C | Torre de refrigeración WT3001C | {"documented":[{"label":"Dimensión X local del contorno CAD","value":5.85,"unit":"m","source":"EQ-CARGAS-20260825 · contorno CAD · handles 525","status":"derivado"},{"label":"Dimensión Y local del contorno CAD","value":2.14,"unit":"m","source":"EQ-CARGAS-20260825 · contorno CAD · handles 525","status":"derivado"},{"label":"Altura acotada","value":3.7,"unit":"m","source":"EQ-CARGAS-20260825 · handle 2659","status":"documentado"},{"label":"Cota relativa de la superficie de apoyo","value":2.0,"unit":"m","source":"LHD2609-JG00100-20260904 · sección 9 / 9-9 / 9A-9A · 2483D, 24841, 24772","status":"documentado"}],"geometry":[{"label":"Extensión de la malla en X","value":6.086959,"unit":"m","source":"Geometría releída del IFC; datum absoluto de proceso provisional","status":"derivado"},{"label":"Extensión de la malla en Y","value":2.9168499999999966,"unit":"m","source":"Geometría releída del IFC; datum absoluto de proceso provisional","status":"derivado"},{"label":"Extensión de la malla en Z","value":3.6999999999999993,"unit":"m","source":"Geometría releída del IFC; datum absoluto de proceso provisional","status":"derivado"},{"label":"Cota inferior de visualización","value":288.1,"unit":"m","source":"Geometría releída del IFC; datum absoluto de proceso provisional","status":"derivado"},{"label":"Cota superior de visualización","value":291.8,"unit":"m","source":"Geometría releída del IFC; datum absoluto de proceso provisional","status":"derivado"}],"notes":["Las extensiones de la malla se miden en los ejes del proyecto tras el giro de implantación; no sustituyen las dimensiones locales del fabricante.","La envolvente, su volumen y los espesores de visualización no son volúmenes de material ni cantidades de compra, construcción o fabricación.","Las dimensiones documentadas distinguen cotas explícitas y medidas extraídas de contornos CAD; las dimensiones geométricas describen únicamente la malla publicada.","Las extensiones de la malla refinada y las dimensiones documentadas del contorno o bastidor tienen distinto alcance; las cotas parciales del detalle son provisionales."]} | {"min":[36.153404,44.224235,3.1],"max":[42.240363,47.141085,6.8]} | {"boundingBoxM":{"min":[36.153404,44.224235,3.1],"max":[42.240363,47.141085,6.8]},"extentsM":[6.086959,2.9168499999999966,3.6999999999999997],"meshSurfaceM2":106.95191032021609,"meshVolumeM3":42.21444620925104,"closedSolid":true,"windingConsistent":true,"basis":"Submalla exacta de los triángulos del modelo IFC coordinado; separación de componentes sin transformación ni retesselación."} | {"id":"WT3001C","sourcePartId":"WT3001C--body","name":"Envolvente del cuerpo de la torre","role":"outer_body_envelope","classificationStatus":"provisional","classificationBasis":"Rol del subvolumen gráfico según el activo de detalle; identidad de fabricación no confirmada.","parentEquipmentId":"WT3001C","parentEquipmentGuid":"2mpg1dx7XLN9c0votd_6ND","isAssemblyIdentityCarrier":true,"sourceFaceRange":[0,12],"sourceCurrentFaceIndices":[0,1,2,3,4,5,6,7,8,9,10,11],"sourceMeshSha256":"7b60c904c9d84d22fded9be34af09a09a9c198ec8e75e61902634d5e4064c761","sourceVertexIndices":[0,1,2,3,4,5,6,7],"separationMethod":"Partición exacta de triángulos existentes; coordenadas y orientación de caras conservadas.","quantityUse":"Magnitudes geométricas del subvolumen; no son cantidades netas de material, fabricación, suministro o capacidad."} | {"status":"componente_independiente","note":"Objeto independiente seleccionable. Las caras se asignan una sola vez entre todos los componentes del conjunto.","parentEquipmentId":"WT3001C","isAssemblyIdentityCarrier":true} | {"id":"WT3001C","name":"Torre de refrigeración WT3001C","relationship":"identity_carrier_with_child_components","parentShapeMeaning":"La forma del objeto que conserva el ID del equipo es únicamente su componente principal; el conjunto completo requiere sus hijos."} | {"elementId":"WT3001C","ifcGuid":"2mpg1dx7XLN9c0votd_6ND","ifcClass":"IfcCoolingTower","buildingId":"process_plant","buildingName":"Planta de proceso","sourceDocumentId":"EQ-CARGAS-20260825","sourceRepresentationKind":"equipmentComponent"} | {"kind":"assembly_documentation","parentEquipmentId":"WT3001C","directAnchorageVerified":false,"note":"La relación del conjunto con cimentaciones se conserva en el objeto que mantiene el ID del equipo; no se atribuye fijación directa a cada subcomponente."} | ["WT3001C","WT3001C--top-frame","WT3001C--fan-ring","WT3001C--blade-01","WT3001C--blade-02","WT3001C--blade-03","WT3001C--blade-04","WT3001C--blade-05","WT3001C--blade-06","WT3001C--fan-hub","WT3001C--lateral-mount-1","WT3001C--lateral-mount-2"] | ["WT3001C--top-frame","WT3001C--fan-ring","WT3001C--blade-01","WT3001C--blade-02","WT3001C--blade-03","WT3001C--blade-04","WT3001C--blade-05","WT3001C--blade-06","WT3001C--fan-hub","WT3001C--lateral-mount-1","WT3001C--lateral-mount-2"] | ["WT3001C--body","WT3001C--top-frame","WT3001C--fan-ring","WT3001C--blade-01","WT3001C--blade-02","WT3001C--blade-03","WT3001C--blade-04","WT3001C--blade-05","WT3001C--blade-06","WT3001C--fan-hub","WT3001C--lateral-mount-1","WT3001C--lateral-mount-2"] | {"Referencia en el plano del fabricante":"9","Identificador del fabricante o del modelo":"WT3001C","Documento de origen":"Plano del fabricante: cargas de equipos · 2026-08-25 · Espacio modelo; número de plano no identificado","Documento CAD derivado":"Conversión DXF del plano de cargas de equipos · 2026-08-25 · espacio modelo","Capa CAD de referencia":"Anotaciones y contornos de equipos","Identificadores CAD del contorno (handles)":"525","Identificador CAD de la cota de altura (handle)":"2659","Cota de altura del fabricante (traducción)":"Altura del equipo: 3.7m","Altura (m)":3.7,"Origen de las dimensiones":"Plano de cargas del fabricante de 2026-08-25: lectura directa del contorno CAD cerrado y de la cota de altura del equipo.","Grado de definición":"Planta derivada del CAD, altura total documentada y alturas parciales provisionales.","Alcance de la geometría":"Geometría compuesta con perfiles CAD y distribución vertical provisional; véase Detalle geométrico.","Origen de la posición":"Punto de referencia del fabricante: entidad CIRCLE, handle 98, en la esquina inferior izquierda de la zona de equipos. Los ejes X e Y son locales y se giran para su implantación UTM.","Hipótesis de modelado":"Nivel de apoyo relativo documentado. Se adopta el cero de proceso a 286,10 m solo para visualización; la equivalencia absoluta no está confirmada. No se añade un espesor de montaje sin cota del fabricante.","Observaciones":"Cuatro unidades adyacentes. El contorno duplicado 523, coincidente con 522, se eliminó. Masa permanente total indicada: 23 000 kg; 5 750 kg por unidad es un reparto aritmético uniforme. La altura corresponde a la envolvente del cuerpo; barandillas y sombreretes de ventiladores no se modelan por separado.","Masa propia indicada (kg)":5750,"Dimensión X local (m)":5.85,"Dimensión Y local (m)":2.14,"Dimensiones de la plataforma de equipos (m)":"27 × 57 m; dimensiones acotadas en el plano general.","Implantación de la plataforma de equipos":"El punto de referencia del fabricante coincide con la esquina suroeste de la zona de equipos. Giro local de −7,82824° para la implantación en coordenadas UTM.","Estado de la cota de instalación":"Nivel de apoyo relativo documentado. Se adopta el cero de proceso a 286,10 m solo para visualización; la equivalencia absoluta no está confirmada. No se añade un espesor de montaje sin cota del fabricante.","Convención de coordenadas":"Coordenadas locales del proyecto en metros. Añadir (729400, 4301550, 285) para recuperar las coordenadas UTM y las cotas del plano.","Identificador del objeto":"WT3001C","Disciplina":"Equipos","Clase IFC":"IfcCoolingTower","Fase del modelo":"Revisión de la zona de separación de aire · septiembre de 2026","Representación geométrica IFC":"Sólido IFC4 mediante malla triangular cerrada","Aplicabilidad a mediciones":"Magnitudes de la geometría representada; no son cantidades de material, obra, compra, capacidad útil ni fabricación. En geometrías compuestas se suman superficies y volúmenes de partes y pueden existir solapes no depurados.","Origen de la masa por unidad":"5 750 kg = 23 000 kg / 4; reparto uniforme derivado, pendiente de confirmar por el fabricante.","Material":"No especificado","Estado de la información":"provisional","Detalle geométrico":"derivado","Incidencias del detalle":["Nivel de apoyo relativo documentado. Se adopta el cero de proceso a 286,10 m solo para visualización; la equivalencia absoluta no está confirmada. No se añade un espesor de montaje sin cota del fabricante.","La masa de 5 750 kg por unidad es el reparto uniforme de 23 000 kg del conjunto; confirmar el reparto real de cargas. Barandillas y sombreretes no se detallan.","El detalle de abril presenta una célula de 5,85 × 2,20 m; el contorno de agosto es de 5,85 × 2,14 m. Se usa el contorno de agosto. El ventilador se traslada al nuevo centro sin alterar su diámetro ni sus palas.","Las cotas intermedias 3,20 / 3,40 / 3,52 / 3,56 m no aparecen acotadas en el fabricante.","Espesor de palas de 0,04 m y altura del aro de 0,30 m: hipótesis de visualización.","La sección y altura reales de la estructura y de los paneles permanecen sin confirmar."],"Extensión X del conjunto refinado en ejes del fabricante (m)":5.85,"Extensión Y del conjunto refinado en ejes del fabricante (m)":2.1400000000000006,"Nivel relativo de apoyo documentado (m)":2.0,"Fuente del nivel de apoyo":{"documentId":"LHD2609-JG00100-20260904","title":"Cimentaciones y pedestales de equipos · revisión recibida 04/09/2026","date":"2026-09-04","sheet":"9 / 9-9 / 9A-9A","sourceHandles":["2483D","24841","24772"]},"Criterio de instalación":"Nivel de apoyo relativo documentado. Se adopta el cero de proceso a 286,10 m solo para visualización; la equivalencia absoluta no está confirmada. No se añade un espesor de montaje sin cota del fabricante."} | 525 | Plano general y dimensiones globales de WT3001C; no se asignan esas dimensiones globales a este componente. | [{"partId":"WT3001C--body","sourceHandles":["525","2659"]},{"partId":"WT3001C--top-frame","sourceHandles":["525","707EC"]},{"partId":"WT3001C--fan-ring","sourceHandles":["707EC","707ED"]},{"partId":"WT3001C--blade-01","sourceHandles":["70928"]},{"partId":"WT3001C--blade-02","sourceHandles":["7093F"]},{"partId":"WT3001C--blade-03","sourceHandles":["70956"]},{"partId":"WT3001C--blade-04","sourceHandles":["70970"]},{"partId":"WT3001C--blade-05","sourceHandles":["7098A"]},{"partId":"WT3001C--blade-06","sourceHandles":["709A0"]},{"partId":"WT3001C--fan-hub","sourceHandles":["709C2"]},{"partId":"WT3001C--lateral-mount-1","sourceHandles":["7080E"]},{"partId":"WT3001C--lateral-mount-2","sourceHandles":["7085E"]}] | WT3001C--body | ["525","2659"]
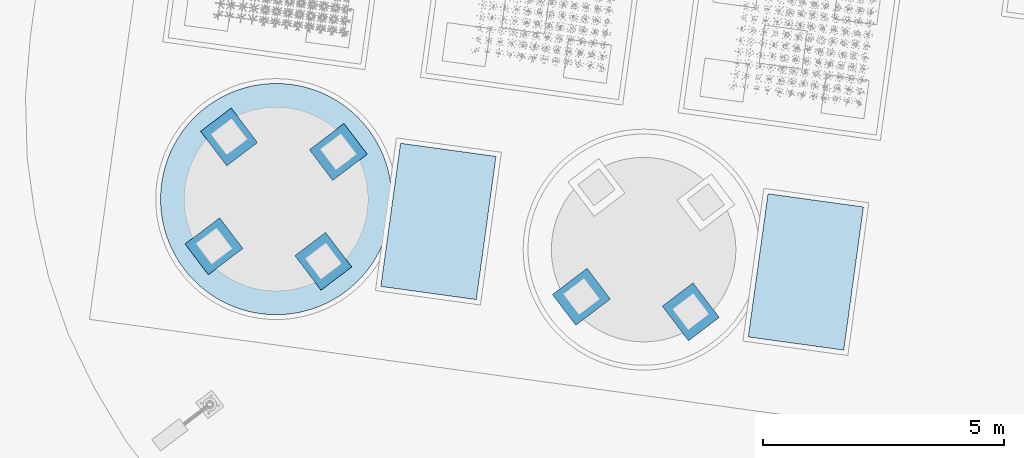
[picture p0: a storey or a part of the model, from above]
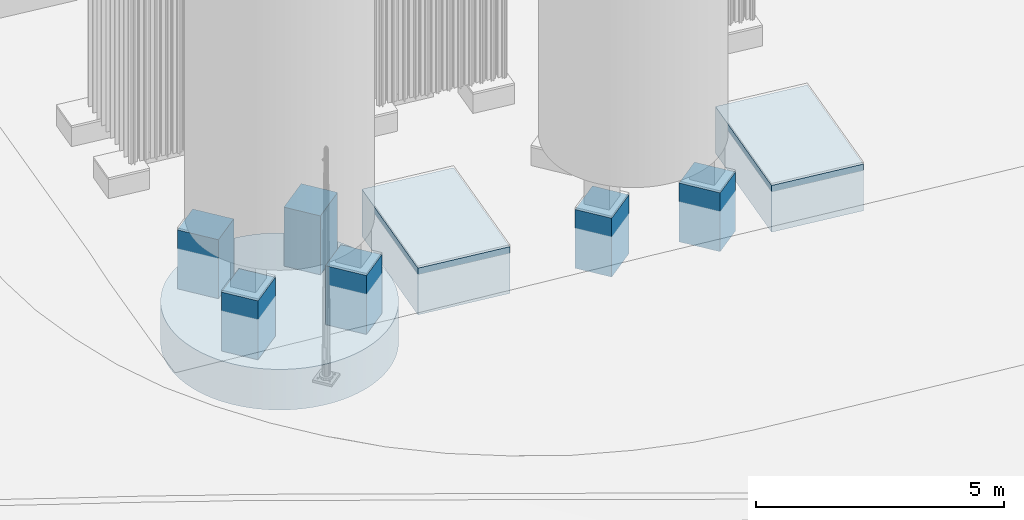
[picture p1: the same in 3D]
Properties of the parts of a building model (IFC4), part 61 of 134

# IfcCoolingTower: Envolvente de equipo (4)
Name | dimensions | JH_InformacionBIM, source = Fuente del componente = DocumentoFuente = JH_DetalleGeometrico, source | positioning = PosicionYEstado | geometryMetrics | detailGeometry | parentEquipmentId = Identificador del fabricante o del modelo = Identificador del objeto = Identificador del elemento = Identificador del equipo padre = Identificador | parentEquipmentName = Equipo padre | parentEquipmentDimensions | assemblyBBox | assemblyGeometryMetrics | component | componentSeparation | assembly | visualizationIdentity | foundationRelationship | componentIds | childComponentIds | sourcePartIds | parentEquipmentProperties | Identificadores CAD del contorno (handles) | Referencia dimensional del conjunto | sourcePartHandles | sourcePartId | sourceHandles
Torre de refrigeración WT3001D · Envolvente del cuerpo de la torre | {"documented":[{"label":"Referencia dimensional del conjunto","value":"Plano general y dimensiones globales de WT3001D; no se asignan esas dimensiones globales a este componente.","unit":"","source":"EQ-CARGAS-20260825 · Espacio modelo","status":"referencia_del_conjunto"}],"geometry":[{"label":"Extensión de la malla en X","value":6.086959,"unit":"m","source":"Geometría releída del IFC; datum absoluto de proceso provisional","status":"derivado"},{"label":"Extensión de la malla en Y","value":2.9168500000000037,"unit":"m","source":"Geometría releída del IFC; datum absoluto de proceso provisional","status":"derivado"},{"label":"Extensión de la malla en Z","value":3.1999999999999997,"unit":"m","source":"Geometría releída del IFC; datum absoluto de proceso provisional","status":"derivado"},{"label":"Cota inferior de visualización","value":288.1,"unit":"m","source":"Geometría releída del IFC; datum absoluto de proceso provisional","status":"derivado"},{"label":"Cota superior de visualización","value":291.3,"unit":"m","source":"Geometría releída del IFC; datum absoluto de proceso provisional","status":"derivado"}],"notes":["Las dimensiones del equipo completo se conservan en parentEquipmentDimensions.","Las extensiones en X/Y son de los ejes del modelo y no sustituyen cotas locales de fabricación.","No se infieren espesores de chapa, tolerancias ni dimensiones de piezas a partir de la partición."]} | {"documentId":"EQ-CARGAS-20260825","title":"Plano del fabricante: cargas de equipos","sheet":"Espacio modelo","date":"2026-08-25","componentSourceHandles":["526","2659"]} | {"Estado de la planta":"Derivado del CAD y del giro de implantación","Nivel relativo del apoyo (m)":2.0,"Estado del nivel relativo":"Documentado en el plano de cimentaciones","Cero absoluto de visualización (m)":286.1,"Estado del cero absoluto":"Provisional","Cota del apoyo de visualización (m)":288.1,"Desplazamiento aplicado a la malla (m)":2.0000000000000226,"Criterio":"Nivel de apoyo relativo documentado. Se adopta el cero de proceso a 286,10 m solo para visualización; la equivalencia absoluta no está confirmada. No se añade un espesor de montaje sin cota del fabricante.","horizontalStatus":"derivado_del_conjunto","verticalStatus":"derivado_del_conjunto","coordinateSystem":"model_local_m","parentEquipmentId":"WT3001D","transformApplied":false,"note":"Coordenadas copiadas exactamente del equipo coordinado; no se ha movido, girado, elevado ni reescalado este componente.","foundationRelationship":"El apoyo y las cotas de instalación se documentan para el conjunto padre. Esta submalla no acredita un anclaje directo.","meshMinimumAbsoluteElevationM":288.1,"assemblyPlacementField":"parentEquipmentPositioning"} | {"boundingBoxM":{"min":[35.861928,42.104178,3.1],"max":[41.948887,45.021028,6.3]},"extentsM":[6.086959,2.91685,3.2],"meshSurfaceM2":76.173998,"meshVolumeM3":40.060799,"closedSolid":true,"basis":"Geometría de coordinación. Los volúmenes de referencia y subcomponentes no son cantidades de material ni componentes de fabricación certificados."} | {"source":{"documentId":"EQ-CARGAS-20260825","title":"Plano del fabricante: cargas de equipos","sheet":"Espacio modelo","date":"2026-08-25","componentSourceHandles":["526","2659"]},"heightSource":{"documentId":"EQ-CARGAS-20260825","title":"Plano del fabricante: cargas de equipos","sheet":"Espacio modelo","date":"2026-08-25"},"revision":"Detalle en planta de 2026-04-30 coordinado de forma preliminar con envolventes y alturas de 2026-08-25","horizontalStatus":"derivado","verticalRule":"Altura total documentada: 3,70 m. Distribución conceptual: cuerpo 0–3,20 m; plataforma superior 3,20–3,40 m; aro del ventilador 3,40–3,70 m; palas 3,52–3,56 m.","status":"Submalla exacta; interpretación funcional y cotas parciales provisionales.","unconfirmedDimensions":["Las cotas intermedias 3,20 / 3,40 / 3,52 / 3,56 m no aparecen acotadas en el fabricante.","Espesor de palas de 0,04 m y altura del aro de 0,30 m: hipótesis de visualización.","La sección y altura reales de la estructura y de los paneles permanecen sin confirmar."],"issues":["El detalle de abril presenta una célula de 5,85 × 2,20 m; el contorno de agosto es de 5,85 × 2,14 m. Se usa el contorno de agosto. El ventilador se traslada al nuevo centro sin alterar su diámetro ni sus palas."],"material":"No especificado","quantityUse":"Magnitudes de la geometría representada; no son cantidades de material, obra, compra, capacidad útil ni fabricación. En geometrías compuestas se suman superficies y volúmenes de partes y pueden existir solapes no depurados.","partsAreBOM":false,"sourceInsertHandle":"83619","partCount":1,"sourcePartHandles":[{"partId":"WT3001D--body","sourceHandles":["526","2659"]},{"partId":"WT3001D--top-frame","sourceHandles":["526","707EC"]},{"partId":"WT3001D--fan-ring","sourceHandles":["707EC","707ED"]},{"partId":"WT3001D--blade-01","sourceHandles":["70928"]},{"partId":"WT3001D--blade-02","sourceHandles":["7093F"]},{"partId":"WT3001D--blade-03","sourceHandles":["70956"]},{"partId":"WT3001D--blade-04","sourceHandles":["70970"]},{"partId":"WT3001D--blade-05","sourceHandles":["7098A"]},{"partId":"WT3001D--blade-06","sourceHandles":["709A0"]},{"partId":"WT3001D--fan-hub","sourceHandles":["709C2"]},{"partId":"WT3001D--lateral-mount-1","sourceHandles":["7080E"]},{"partId":"WT3001D--lateral-mount-2","sourceHandles":["7085E"]}],"actualExtentManufacturerAxesM":[5.85,2.14,3.7],"sourcePartId":"WT3001D--body","sourceHandles":["526","2659"]} | WT3001D | Torre de refrigeración WT3001D | {"documented":[{"label":"Dimensión X local del contorno CAD","value":5.85,"unit":"m","source":"EQ-CARGAS-20260825 · contorno CAD · handles 526","status":"derivado"},{"label":"Dimensión Y local del contorno CAD","value":2.14,"unit":"m","source":"EQ-CARGAS-20260825 · contorno CAD · handles 526","status":"derivado"},{"label":"Altura acotada","value":3.7,"unit":"m","source":"EQ-CARGAS-20260825 · handle 2659","status":"documentado"},{"label":"Cota relativa de la superficie de apoyo","value":2.0,"unit":"m","source":"LHD2609-JG00100-20260904 · sección 9 / 9-9 / 9A-9A · 2483D, 24841, 24772","status":"documentado"}],"geometry":[{"label":"Extensión de la malla en X","value":6.086959,"unit":"m","source":"Geometría releída del IFC; datum absoluto de proceso provisional","status":"derivado"},{"label":"Extensión de la malla en Y","value":2.9168500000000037,"unit":"m","source":"Geometría releída del IFC; datum absoluto de proceso provisional","status":"derivado"},{"label":"Extensión de la malla en Z","value":3.6999999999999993,"unit":"m","source":"Geometría releída del IFC; datum absoluto de proceso provisional","status":"derivado"},{"label":"Cota inferior de visualización","value":288.1,"unit":"m","source":"Geometría releída del IFC; datum absoluto de proceso provisional","status":"derivado"},{"label":"Cota superior de visualización","value":291.8,"unit":"m","source":"Geometría releída del IFC; datum absoluto de proceso provisional","status":"derivado"}],"notes":["Las extensiones de la malla se miden en los ejes del proyecto tras el giro de implantación; no sustituyen las dimensiones locales del fabricante.","La envolvente, su volumen y los espesores de visualización no son volúmenes de material ni cantidades de compra, construcción o fabricación.","Las dimensiones documentadas distinguen cotas explícitas y medidas extraídas de contornos CAD; las dimensiones geométricas describen únicamente la malla publicada.","Las extensiones de la malla refinada y las dimensiones documentadas del contorno o bastidor tienen distinto alcance; las cotas parciales del detalle son provisionales."]} | {"min":[35.861928,42.104178,3.1],"max":[41.948887,45.021028,6.8]} | {"boundingBoxM":{"min":[35.861928,42.104178,3.1],"max":[41.948887,45.021028,6.8]},"extentsM":[6.086959,2.9168500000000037,3.6999999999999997],"meshSurfaceM2":106.95190117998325,"meshVolumeM3":42.214443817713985,"closedSolid":true,"windingConsistent":true,"basis":"Submalla exacta de los triángulos del modelo IFC coordinado; separación de componentes sin transformación ni retesselación."} | {"id":"WT3001D","sourcePartId":"WT3001D--body","name":"Envolvente del cuerpo de la torre","role":"outer_body_envelope","classificationStatus":"provisional","classificationBasis":"Rol del subvolumen gráfico según el activo de detalle; identidad de fabricación no confirmada.","parentEquipmentId":"WT3001D","parentEquipmentGuid":"2AZFhKNMnMognqXDVjGcnW","isAssemblyIdentityCarrier":true,"sourceFaceRange":[0,12],"sourceCurrentFaceIndices":[0,1,2,3,4,5,6,7,8,9,10,11],"sourceMeshSha256":"7b60c904c9d84d22fded9be34af09a09a9c198ec8e75e61902634d5e4064c761","sourceVertexIndices":[0,1,2,3,4,5,6,7],"separationMethod":"Partición exacta de triángulos existentes; coordenadas y orientación de caras conservadas.","quantityUse":"Magnitudes geométricas del subvolumen; no son cantidades netas de material, fabricación, suministro o capacidad."} | {"status":"componente_independiente","note":"Objeto independiente seleccionable. Las caras se asignan una sola vez entre todos los componentes del conjunto.","parentEquipmentId":"WT3001D","isAssemblyIdentityCarrier":true} | {"id":"WT3001D","name":"Torre de refrigeración WT3001D","relationship":"identity_carrier_with_child_components","parentShapeMeaning":"La forma del objeto que conserva el ID del equipo es únicamente su componente principal; el conjunto completo requiere sus hijos."} | {"elementId":"WT3001D","ifcGuid":"2AZFhKNMnMognqXDVjGcnW","ifcClass":"IfcCoolingTower","buildingId":"process_plant","buildingName":"Planta de proceso","sourceDocumentId":"EQ-CARGAS-20260825","sourceRepresentationKind":"equipmentComponent"} | {"kind":"assembly_documentation","parentEquipmentId":"WT3001D","directAnchorageVerified":false,"note":"La relación del conjunto con cimentaciones se conserva en el objeto que mantiene el ID del equipo; no se atribuye fijación directa a cada subcomponente."} | ["WT3001D","WT3001D--top-frame","WT3001D--fan-ring","WT3001D--blade-01","WT3001D--blade-02","WT3001D--blade-03","WT3001D--blade-04","WT3001D--blade-05","WT3001D--blade-06","WT3001D--fan-hub","WT3001D--lateral-mount-1","WT3001D--lateral-mount-2"] | ["WT3001D--top-frame","WT3001D--fan-ring","WT3001D--blade-01","WT3001D--blade-02","WT3001D--blade-03","WT3001D--blade-04","WT3001D--blade-05","WT3001D--blade-06","WT3001D--fan-hub","WT3001D--lateral-mount-1","WT3001D--lateral-mount-2"] | ["WT3001D--body","WT3001D--top-frame","WT3001D--fan-ring","WT3001D--blade-01","WT3001D--blade-02","WT3001D--blade-03","WT3001D--blade-04","WT3001D--blade-05","WT3001D--blade-06","WT3001D--fan-hub","WT3001D--lateral-mount-1","WT3001D--lateral-mount-2"] | {"Referencia en el plano del fabricante":"9","Identificador del fabricante o del modelo":"WT3001D","Documento de origen":"Plano del fabricante: cargas de equipos · 2026-08-25 · Espacio modelo; número de plano no identificado","Documento CAD derivado":"Conversión DXF del plano de cargas de equipos · 2026-08-25 · espacio modelo","Capa CAD de referencia":"Anotaciones y contornos de equipos","Identificadores CAD del contorno (handles)":"526","Identificador CAD de la cota de altura (handle)":"2659","Cota de altura del fabricante (traducción)":"Altura del equipo: 3.7m","Altura (m)":3.7,"Origen de las dimensiones":"Plano de cargas del fabricante de 2026-08-25: lectura directa del contorno CAD cerrado y de la cota de altura del equipo.","Grado de definición":"Planta derivada del CAD, altura total documentada y alturas parciales provisionales.","Alcance de la geometría":"Geometría compuesta con perfiles CAD y distribución vertical provisional; véase Detalle geométrico.","Origen de la posición":"Punto de referencia del fabricante: entidad CIRCLE, handle 98, en la esquina inferior izquierda de la zona de equipos. Los ejes X e Y son locales y se giran para su implantación UTM.","Hipótesis de modelado":"Nivel de apoyo relativo documentado. Se adopta el cero de proceso a 286,10 m solo para visualización; la equivalencia absoluta no está confirmada. No se añade un espesor de montaje sin cota del fabricante.","Observaciones":"Cuatro unidades adyacentes. El contorno duplicado 523, coincidente con 522, se eliminó. Masa permanente total indicada: 23 000 kg; 5 750 kg por unidad es un reparto aritmético uniforme. La altura corresponde a la envolvente del cuerpo; barandillas y sombreretes de ventiladores no se modelan por separado.","Masa propia indicada (kg)":5750,"Dimensión X local (m)":5.85,"Dimensión Y local (m)":2.14,"Dimensiones de la plataforma de equipos (m)":"27 × 57 m; dimensiones acotadas en el plano general.","Implantación de la plataforma de equipos":"El punto de referencia del fabricante coincide con la esquina suroeste de la zona de equipos. Giro local de −7,82824° para la implantación en coordenadas UTM.","Estado de la cota de instalación":"Nivel de apoyo relativo documentado. Se adopta el cero de proceso a 286,10 m solo para visualización; la equivalencia absoluta no está confirmada. No se añade un espesor de montaje sin cota del fabricante.","Convención de coordenadas":"Coordenadas locales del proyecto en metros. Añadir (729400, 4301550, 285) para recuperar las coordenadas UTM y las cotas del plano.","Identificador del objeto":"WT3001D","Disciplina":"Equipos","Clase IFC":"IfcCoolingTower","Fase del modelo":"Revisión de la zona de separación de aire · septiembre de 2026","Representación geométrica IFC":"Sólido IFC4 mediante malla triangular cerrada","Aplicabilidad a mediciones":"Magnitudes de la geometría representada; no son cantidades de material, obra, compra, capacidad útil ni fabricación. En geometrías compuestas se suman superficies y volúmenes de partes y pueden existir solapes no depurados.","Origen de la masa por unidad":"5 750 kg = 23 000 kg / 4; reparto uniforme derivado, pendiente de confirmar por el fabricante.","Material":"No especificado","Estado de la información":"provisional","Detalle geométrico":"derivado","Incidencias del detalle":["Nivel de apoyo relativo documentado. Se adopta el cero de proceso a 286,10 m solo para visualización; la equivalencia absoluta no está confirmada. No se añade un espesor de montaje sin cota del fabricante.","La masa de 5 750 kg por unidad es el reparto uniforme de 23 000 kg del conjunto; confirmar el reparto real de cargas. Barandillas y sombreretes no se detallan.","El detalle de abril presenta una célula de 5,85 × 2,20 m; el contorno de agosto es de 5,85 × 2,14 m. Se usa el contorno de agosto. El ventilador se traslada al nuevo centro sin alterar su diámetro ni sus palas.","Las cotas intermedias 3,20 / 3,40 / 3,52 / 3,56 m no aparecen acotadas en el fabricante.","Espesor de palas de 0,04 m y altura del aro de 0,30 m: hipótesis de visualización.","La sección y altura reales de la estructura y de los paneles permanecen sin confirmar."],"Extensión X del conjunto refinado en ejes del fabricante (m)":5.85,"Extensión Y del conjunto refinado en ejes del fabricante (m)":2.139999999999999,"Nivel relativo de apoyo documentado (m)":2.0,"Fuente del nivel de apoyo":{"documentId":"LHD2609-JG00100-20260904","title":"Cimentaciones y pedestales de equipos · revisión recibida 04/09/2026","date":"2026-09-04","sheet":"9 / 9-9 / 9A-9A","sourceHandles":["2483D","24841","24772"]},"Criterio de instalación":"Nivel de apoyo relativo documentado. Se adopta el cero de proceso a 286,10 m solo para visualización; la equivalencia absoluta no está confirmada. No se añade un espesor de montaje sin cota del fabricante."} | 526 | Plano general y dimensiones globales de WT3001D; no se asignan esas dimensiones globales a este componente. | [{"partId":"WT3001D--body","sourceHandles":["526","2659"]},{"partId":"WT3001D--top-frame","sourceHandles":["526","707EC"]},{"partId":"WT3001D--fan-ring","sourceHandles":["707EC","707ED"]},{"partId":"WT3001D--blade-01","sourceHandles":["70928"]},{"partId":"WT3001D--blade-02","sourceHandles":["7093F"]},{"partId":"WT3001D--blade-03","sourceHandles":["70956"]},{"partId":"WT3001D--blade-04","sourceHandles":["70970"]},{"partId":"WT3001D--blade-05","sourceHandles":["7098A"]},{"partId":"WT3001D--blade-06","sourceHandles":["709A0"]},{"partId":"WT3001D--fan-hub","sourceHandles":["709C2"]},{"partId":"WT3001D--lateral-mount-1","sourceHandles":["7080E"]},{"partId":"WT3001D--lateral-mount-2","sourceHandles":["7085E"]}] | WT3001D--body | ["526","2659"]

# IfcCovering (2)
In: Planta baja
Description: Capa de acabado o aislamiento; Document: Planos de arquitectura del edificio de oficinas; Planos de arquitectura del edificio de oficinas; Group: Arquitectura; BIM · Arquitectura
JH_MagnitudesGeometricas - ExtensionX: 12.6309 m; ExtensionY: 21.1757 m
JH_InformacionBIM - buildingId: office; buildingName: Edificio de oficinas; level: Planta baja; category: Capa de acabado o aislamiento; ifcClass: IfcCovering; source: {"documentId":"ARQ-OF-20260710","title":"Planos de arquitectura del edificio de oficinas","date":"2026-07-10","sheet":"Arquitectura A202 / p. 13"}; status: derivado; issues: ["El plano general de 2026-07-31 mantiene el edificio de oficinas de 200 m², mientras documentación anterior indica su supresión. Se conserva lo dibujado, pendiente de confirmación de la propiedad y del equipo de diseño.","Registro de líneas del PDF general, envolvente de 20 × 10 m; eje local 1 al norte y acceso del lado A al oeste. Estimación de trabajo de implantación de ±0,15 m, pendiente de CAD; no constituye una precisión topográfica garantizada."]; positioning: {"horizontalStatus":"derivado","verticalStatus":"derivado","baseElevationM":285.95,"note":"Registro de líneas del PDF general, envolvente de 20 × 10 m; eje local 1 al norte y acceso del lado A al oeste. Estimación de trabajo de implantación de ±0,15 m, pendiente de CAD; no constituye una precisión topográfica garantizada."}; ifcAssociations: {"material":true,"document":true,"quantities":true,"containerGuid":"3ztlotcerHPueDgxP84R6z","containerName":"Planta baja"}; visualLayer: {"id":"architecture","name":"Arquitectura"}; componentSeparation: {"status":"objeto_independiente","note":"Control de visibilidad del objeto completo; la clasificación no altera la malla."}; classification: {"layerId":"architecture","layerName":"Arquitectura","role":"Capa de acabado o aislamiento","basis":"Clasificación por función del elemento; no modifica las especificaciones documentales."}; layerId: architecture
JH_Trazabilidad - Planos de referencia: ARQ-OF-20260710 · Arquitectura A202 / p. 13; Edificio: Edificio de oficinas; Sistema de coordenadas: Coordenadas de proyecto en metros; sumar (729400, 4301550, 285) para recuperar las coordenadas UTM y cotas de los planos.; Uso del modelo: Reconstrucción tridimensional de la documentación y revisión preliminar de coordinación; pendiente de revisión por el equipo de diseño.; Verificación de la malla: Malla cerrada, orientación coherente de las caras y volumen positivo.; Referencia de implantación: Plano general U004 de 2026-07-31; geometría vectorial del PDF registrada con las coordenadas de lindero indicadas.; Estado de la implantación: Registro de líneas del PDF general, envolvente de 20 × 10 m; eje local 1 al norte y acceso del lado A al oeste. Estimación de trabajo de implantación de ±0,15 m, pendiente de CAD; no constituye una precisión topográfica garantizada.; Discrepancia entre versiones: El plano general de 2026-07-31 mantiene el edificio de oficinas de 200 m², mientras documentación anterior indica su supresión. Se conserva lo dibujado, pendiente de confirmación de la propiedad y del equipo de diseño.; Disciplina: Arquitectura; Clase IFC: IfcCovering; Fase del modelo: V0.1 · Reconstrucción documental y coordinación preliminar; Representación geométrica: Sólido de malla triangular cerrada en IFC4; Aplicabilidad de las mediciones: Volumen exclusivamente geométrico; los espesores de representación, las simplificaciones y las envolventes no constituyen mediciones de compra, ejecución, fabricación ni volumen neto de material.; Referencia del material: ARQ-OF-20260710 · Arquitectura A202 / p. 13; Cota de planta baja terminada (m): 285.95; Capa BIM: Arquitectura; Estado del acabado: criterio_visual; Categoria: Capa de acabado o aislamiento; ClaseIFC: IfcCovering; EstadoDeInformacion: derivado; DocumentoFuente: {"documentId":"ARQ-OF-20260710","title":"Planos de arquitectura del edificio de oficinas","date":"2026-07-10","sheet":"Arquitectura A202 / p. 13"}; IncidenciasPendientes: ["El plano general de 2026-07-31 mantiene el edificio de oficinas de 200 m², mientras documentación anterior indica su supresión. Se conserva lo dibujado, pendiente de confirmación de la propiedad y del equipo de diseño.","Registro de líneas del PDF general, envolvente de 20 × 10 m; eje local 1 al norte y acceso del lado A al oeste. Estimación de trabajo de implantación de ±0,15 m, pendiente de CAD; no constituye una precisión topográfica garantizada."]; UsoDeLasMagnitudes: Geometría de coordinación. Los volúmenes de referencia y subcomponentes no son cantidades de material ni componentes de fabricación certificados.
JH_CriterioDePosicion - PosicionYEstado: {"horizontalStatus":"derivado","verticalStatus":"derivado","baseElevationM":285.95,"note":"Registro de líneas del PDF general, envolvente de 20 × 10 m; eje local 1 al norte y acceso del lado A al oeste. Estimación de trabajo de implantación de ±0,15 m, pendiente de CAD; no constituye una precisión topográfica garantizada."}
JH_EvidenciaDeMaterial - source: ARQ-OF-20260710 · Arquitectura A202 / p. 13; status: known
JH_CapaBIM - IdentificadorCapa: architecture; NombreCapa: Arquitectura; Funcion: Capa de acabado o aislamiento; VisibilidadInicial: yes
JH_AcabadoVisual - Metallicidad: 0; Estado: criterio_visual; Referencia: Interpretación visual del material documental; el acabado, tono y parámetros PBR no son una especificación contractual.; Nota: La apariencia no certifica el material físico ni el acabado de fabricación.
Name | PredefinedType | Material = JH_Trazabilidad, Material = name | Dimensiones de la caja local del elemento (X, Y, Z) | Cota mínima absoluta de la malla (m) | Cota máxima absoluta de la malla (m) | Volumen geométrico bruto (m3) = VolumenGeometrico (m3) = Volumen geométrico (m³) | Reference = Identificador del elemento = Identificador | ExtensionZ (m) = Espesor (m) = Espesor (m) | SuperficieDeLaMalla (m2) | material | dimensions | geometryMetrics | materialAppearance | visualizationIdentity | appearance | Base geométrica | Acabado de visualización = Acabado | Perfil | ColorRGB | Rugosidad
Aislamiento XPS del pavimento de oficinas · 100 mm | INSULATION | Poliestireno extruido XPS | 20 × 10 × 0.1 | 285.81 | 285.91 | 20 | office_0208 | 0.1 | 406 | {"name":"Poliestireno extruido XPS","source":"ARQ-OF-20260710 · Arquitectura A202 / p. 13","status":"known"} | {"documented":[{"label":"Espesor","value":0.1,"unit":"m","source":"ARQ-OF-20260710 · Arquitectura A202 / p. 13","status":"documentado"}],"geometry":[{"label":"Dimensiones de la caja local del elemento (X, Y, Z)","value":"20 × 10 × 0.1","unit":"m","source":"Malla triangulada del elemento en ejes locales del edificio","status":"derivado"},{"label":"Cota mínima absoluta de la malla","value":285.81,"unit":"m","source":"Malla de proyecto y origen altimétrico 285 m","status":"derivado"},{"label":"Cota máxima absoluta de la malla","value":285.91,"unit":"m","source":"Malla de proyecto y origen altimétrico 285 m","status":"derivado"},{"label":"Volumen geométrico bruto","value":20.0,"unit":"m³","source":"Malla cerrada del elemento","status":"derivado"}],"notes":["Las dimensiones documentadas proceden de anotaciones o cuadros; la caja y el volumen se calculan a partir de la malla.","El volumen es exclusivamente geométrico y bruto; no representa una medición neta de material ni una cantidad de compra."]} | {"boundingBoxM":{"min":[14.818557,71.742172,0.81],"max":[27.449443,92.917828,0.91]},"extentsM":[12.630886,21.175656,0.1],"meshSurfaceM2":406.0,"meshVolumeM3":20.0,"closedSolid":true,"basis":"Geometría triangulada releída del IFC; envolventes y magnitudes no contractuales."} | {"profileId":"xps","name":"Aislamiento XPS","materialName":"Poliestireno extruido XPS","physicalMaterialStatus":"known","physicalMaterialSource":"ARQ-OF-20260710 · Arquitectura A202 / p. 13","appearanceStatus":"criterio_visual","appearanceBasis":"Interpretación visual del material documental; el acabado, tono y parámetros PBR no son una especificación contractual.","note":"La apariencia gráfica no modifica ni confirma la especificación física del material."} | {"elementId":"office_0208","ifcGuid":"38hiyRfrLVogcQ1qfYyMIQ","ifcClass":"IfcCovering","buildingId":"office","buildingName":"Edificio de oficinas","sourceDocumentId":"ARQ-OF-20260710","sourceRepresentationKind":"documentary_mesh"} | {"profileId":"xps","name":"Aislamiento XPS","status":"criterio_visual","basis":"Interpretación visual del material documental; el acabado, tono y parámetros PBR no son una especificación contractual.","physicalMaterialUnchanged":true} | Espesor de 100 mm documentado; posición deducida bajo el acabado del pavimento. | Aislamiento XPS | xps | [0.741176,0.780392,0.717647] | 0.92
Mortero y baldosa del pavimento de oficinas | FLOORING | Mortero de cemento y baldosa cerámica | 20 × 10 × 0.04 | 285.91 | 285.95 | 8 | office_0209 | 0.04 | 402.4 | {"name":"Mortero de cemento y baldosa cerámica","source":"ARQ-OF-20260710 · Arquitectura A202 / p. 13","status":"known"} | {"documented":[{"label":"Espesor","value":0.04,"unit":"m","source":"ARQ-OF-20260710 · Arquitectura A202 / p. 13","status":"documentado"}],"geometry":[{"label":"Dimensiones de la caja local del elemento (X, Y, Z)","value":"20 × 10 × 0.04","unit":"m","source":"Malla triangulada del elemento en ejes locales del edificio","status":"derivado"},{"label":"Cota mínima absoluta de la malla","value":285.91,"unit":"m","source":"Malla de proyecto y origen altimétrico 285 m","status":"derivado"},{"label":"Cota máxima absoluta de la malla","value":285.95,"unit":"m","source":"Malla de proyecto y origen altimétrico 285 m","status":"derivado"},{"label":"Volumen geométrico bruto","value":8.0,"unit":"m³","source":"Malla cerrada del elemento","status":"derivado"}],"notes":["Las dimensiones documentadas proceden de anotaciones o cuadros; la caja y el volumen se calculan a partir de la malla.","El volumen es exclusivamente geométrico y bruto; no representa una medición neta de material ni una cantidad de compra."]} | {"boundingBoxM":{"min":[14.818557,71.742172,0.91],"max":[27.449443,92.917828,0.95]},"extentsM":[12.630886,21.175656,0.04],"meshSurfaceM2":402.4,"meshVolumeM3":8.0,"closedSolid":true,"basis":"Geometría triangulada releída del IFC; envolventes y magnitudes no contractuales."} | {"profileId":"ceramic_tile","name":"Pavimento cerámico","materialName":"Mortero de cemento y baldosa cerámica","physicalMaterialStatus":"known","physicalMaterialSource":"ARQ-OF-20260710 · Arquitectura A202 / p. 13","appearanceStatus":"criterio_visual","appearanceBasis":"Interpretación visual del material documental; el acabado, tono y parámetros PBR no son una especificación contractual.","note":"La apariencia gráfica no modifica ni confirma la especificación física del material."} | {"elementId":"office_0209","ifcGuid":"02yYT6NwHQWQutvOvq48jb","ifcClass":"IfcCovering","buildingId":"office","buildingName":"Edificio de oficinas","sourceDocumentId":"ARQ-OF-20260710","sourceRepresentationKind":"documentary_mesh"} | {"profileId":"ceramic_tile","name":"Pavimento cerámico","status":"criterio_visual","basis":"Interpretación visual del material documental; el acabado, tono y parámetros PBR no son una especificación contractual.","physicalMaterialUnchanged":true} | Zona de oficinas: 30 mm de mortero y 10 mm de baldosa; no se han diferenciado los acabados de los aseos. | Pavimento cerámico | ceramic_tile | [0.764706,0.752941,0.717647] | 0.5

# IfcDoor (4)
In: Planta baja
Description: Puerta exterior; PredefinedType: DOOR; Group: Arquitectura; BIM · Arquitectura
JH_DimensionesDelModelo - Espesor utilizado para representación: 0.04 m
Pset_DoorCommon - IsExternal: yes
JH_InformacionBIM - level: Planta baja; category: Puerta exterior; ifcClass: IfcDoor; status: provisional; visualLayer: {"id":"architecture","name":"Arquitectura"}; componentSeparation: {"status":"objeto_independiente","note":"Control de visibilidad del objeto completo; la clasificación no altera la malla."}; classification: {"layerId":"architecture","layerName":"Arquitectura","role":"Puerta exterior","basis":"Clasificación por función del elemento; no modifica las especificaciones documentales."}; layerId: architecture
JH_Trazabilidad - Base geométrica: Anchura y altura del hueco según planos; espesor de carpintería aproximado para visualización.; Sistema de coordenadas: Coordenadas de proyecto en metros; sumar (729400, 4301550, 285) para recuperar las coordenadas UTM y cotas de los planos.; Uso del modelo: Reconstrucción tridimensional de la documentación y revisión preliminar de coordinación; pendiente de revisión por el equipo de diseño.; Altura de antepecho (m): 0; Espesor de representación (m): 0.04; Representación de la carpintería: Elemento representado por un sólido cerrado único; perfiles de marco y hoja sin detalle de fabricación.; Verificación de la malla: Malla cerrada, orientación coherente de las caras y volumen positivo.; Referencia de implantación: Plano general U004 de 2026-07-31; geometría vectorial del PDF registrada con las coordenadas de lindero indicadas.; Disciplina: Arquitectura; Clase IFC: IfcDoor; Fase del modelo: V0.1 · Reconstrucción documental y coordinación preliminar; Representación geométrica: Sólido de malla triangular cerrada en IFC4; Aplicabilidad de las mediciones: Volumen exclusivamente geométrico; los espesores de representación, las simplificaciones y las envolventes no constituyen mediciones de compra, ejecución, fabricación ni volumen neto de material.; Capa BIM: Arquitectura; Estado del acabado: criterio_visual; Categoria: Puerta exterior; ClaseIFC: IfcDoor; EstadoDeInformacion: provisional; UsoDeLasMagnitudes: Geometría de coordinación. Los volúmenes de referencia y subcomponentes no son cantidades de material ni componentes de fabricación certificados.
JH_EvidenciaDeMaterial - status: known
JH_DimensionesDocumentadas - Altura de antepecho: 0 m
JH_CapaBIM - IdentificadorCapa: architecture; NombreCapa: Arquitectura; Funcion: Puerta exterior; VisibilidadInicial: yes
JH_AcabadoVisual - Estado: criterio_visual; Referencia: Interpretación visual del material documental; el acabado, tono y parámetros PBR no son una especificación contractual.; Nota: La apariencia no certifica el material físico ni el acabado de fabricación.
Name | Document | Material = JH_Trazabilidad, Material = name | Dimensiones de la caja local del elemento (X, Y, Z) | Cota mínima absoluta de la malla (m) = Cota de planta baja terminada (m) | Cota máxima absoluta de la malla (m) | Volumen geométrico bruto (m3) = Volumen geométrico (m³) | Reference = Identificador del elemento = Identificador | ExtensionX (m) | ExtensionY (m) | ExtensionZ (m) = Altura del hueco (m) = Altura del hueco (m) | SuperficieDeLaMalla (m2) | VolumenGeometrico (m3) | buildingId | buildingName = Edificio | material | dimensions | JH_InformacionBIM, source = DocumentoFuente | issues = IncidenciasPendientes | positioning = PosicionYEstado | commonProperties | geometryMetrics | ifcAssociations | materialAppearance | visualizationIdentity | appearance | Planos de referencia | Tipo de carpintería | Anchura del hueco (m) = Anchura del hueco (m) | Estado de la implantación | Referencia del material = JH_EvidenciaDeMaterial, source | Acabado de visualización = Acabado | Perfil | ColorRGB | Rugosidad | Metallicidad
Sala de bombas contra incendios · puerta JLM4026 | Planos de arquitectura de la sala de bombas contra incendios; Planos de arquitectura de la sala de bombas contra incendios | Aluminio | 4 × 0.04 × 2.6 | 286.25 | 288.85 | 0.416 | pump_house_0040 | 3.96817 | 0.584443 | 2.6 | 21.328 | 0.416003 | pump_house | Sala de bombas contra incendios | {"name":"Aluminio","source":"ARQ-SB-20260710 · A109 / p. 11 y A110 / p. 12","status":"known"} | {"documented":[{"label":"Anchura del hueco","value":4,"unit":"m","source":"ARQ-SB-20260710 · Arquitectura A101 / p. 3; Carpinterías A109 / p. 11, A110 / p. 12","status":"documentado"},{"label":"Altura del hueco","value":2.6,"unit":"m","source":"ARQ-SB-20260710 · Arquitectura A101 / p. 3; Carpinterías A109 / p. 11, A110 / p. 12","status":"documentado"},{"label":"Altura de antepecho","value":0,"unit":"m","source":"ARQ-SB-20260710 · Arquitectura A101 / p. 3; Carpinterías A109 / p. 11, A110 / p. 12","status":"documentado"}],"geometry":[{"label":"Dimensiones de la caja local del elemento (X, Y, Z)","value":"4 × 0.04 × 2.6","unit":"m","source":"Malla triangulada del elemento en ejes locales del edificio","status":"derivado"},{"label":"Cota mínima absoluta de la malla","value":286.25,"unit":"m","source":"Malla de proyecto y origen altimétrico 285 m","status":"derivado"},{"label":"Cota máxima absoluta de la malla","value":288.85,"unit":"m","source":"Malla de proyecto y origen altimétrico 285 m","status":"derivado"},{"label":"Volumen geométrico bruto","value":0.416,"unit":"m³","source":"Malla cerrada del elemento","status":"derivado"},{"label":"Espesor utilizado para representación","value":0.04,"unit":"m","source":"Hipótesis de visualización, no dimensión de fabricación","status":"provisional"}],"notes":["Las dimensiones documentadas proceden de anotaciones o cuadros; la caja y el volumen se calculan a partir de la malla.","El volumen es exclusivamente geométrico y bruto; no representa una medición neta de material ni una cantidad de compra."]} | {"documentId":"ARQ-SB-20260710","title":"Planos de arquitectura de la sala de bombas contra incendios","date":"2026-07-10","sheet":"Arquitectura A101 / p. 3; Carpinterías A109 / p. 11, A110 / p. 12"} | ["Elemento representado por un sólido cerrado único; perfiles de marco y hoja sin detalle de fabricación.","Registro de líneas del PDF general con envolvente de 10,2 × 8,2 m. Estimación de trabajo de implantación de ±0,15 m, pendiente de CAD nativo; no constituye una precisión topográfica garantizada."] | {"horizontalStatus":"derivado","verticalStatus":"provisional","baseElevationM":286.25,"note":"Registro de líneas del PDF general con envolvente de 10,2 × 8,2 m. Estimación de trabajo de implantación de ±0,15 m, pendiente de CAD nativo; no constituye una precisión topográfica garantizada."} | {"Pset_DoorCommon":{"IsExternal":{"value":true,"source":"ARQ-SB-20260710 · A101, A103 y alzados; elemento de la envolvente exterior identificada en planta","status":"known"}}} | {"boundingBoxM":{"min":[11.594253,33.926845,1.25],"max":[15.562425,34.511288,3.85]},"extentsM":[3.968172,0.584443,2.6],"meshSurfaceM2":21.328005,"meshVolumeM3":0.416003,"closedSolid":true,"basis":"Geometría triangulada releída del IFC; envolventes y magnitudes no contractuales."} | {"material":true,"document":true,"quantities":true,"containerGuid":"0Wh59pm9LO_einrwiq6Es1","containerName":"Planta baja"} | {"profileId":"aluminum","name":"Aluminio satinado","materialName":"Aluminio","physicalMaterialStatus":"known","physicalMaterialSource":"ARQ-SB-20260710 · A109 / p. 11 y A110 / p. 12","appearanceStatus":"criterio_visual","appearanceBasis":"Interpretación visual del material documental; el acabado, tono y parámetros PBR no son una especificación contractual.","note":"La apariencia gráfica no modifica ni confirma la especificación física del material."} | {"elementId":"pump_house_0040","ifcGuid":"2o$ASZwivIZ96CeDSyk90a","ifcClass":"IfcDoor","buildingId":"pump_house","buildingName":"Sala de bombas contra incendios","sourceDocumentId":"ARQ-SB-20260710","sourceRepresentationKind":"documentary_mesh"} | {"profileId":"aluminum","name":"Aluminio satinado","status":"criterio_visual","basis":"Interpretación visual del material documental; el acabado, tono y parámetros PBR no son una especificación contractual.","physicalMaterialUnchanged":true} | ARQ-SB-20260710 · Arquitectura A101 / p. 3; Carpinterías A109 / p. 11, A110 / p. 12 | Puerta enrollable | 4 | Registro de líneas del PDF general con envolvente de 10,2 × 8,2 m. Estimación de trabajo de implantación de ±0,15 m, pendiente de CAD nativo; no constituye una precisión topográfica garantizada. | ARQ-SB-20260710 · A109 / p. 11 y A110 / p. 12 | Aluminio satinado | aluminum | [0.74902,0.784314,0.796078] | 0.35 | 0.75
Sala de bombas contra incendios · puerta WM1523 | Planos de arquitectura de la sala de bombas contra incendios; Planos de arquitectura de la sala de bombas contra incendios | Acero lacado | 1.5 × 0.04 × 2.3 | 286.25 | 288.55 | 0.138 | pump_house_0041 | 1.49147 | 0.243933 | 2.3 | 7.204 | 0.137999 | pump_house | Sala de bombas contra incendios | {"name":"Acero lacado","source":"ARQ-SB-20260710 · A109 / p. 11","status":"known"} | {"documented":[{"label":"Anchura del hueco","value":1.5,"unit":"m","source":"ARQ-SB-20260710 · Arquitectura A101 / p. 3; Carpinterías A109 / p. 11, A110 / p. 12","status":"documentado"},{"label":"Altura del hueco","value":2.3,"unit":"m","source":"ARQ-SB-20260710 · Arquitectura A101 / p. 3; Carpinterías A109 / p. 11, A110 / p. 12","status":"documentado"},{"label":"Altura de antepecho","value":0,"unit":"m","source":"ARQ-SB-20260710 · Arquitectura A101 / p. 3; Carpinterías A109 / p. 11, A110 / p. 12","status":"documentado"}],"geometry":[{"label":"Dimensiones de la caja local del elemento (X, Y, Z)","value":"1.5 × 0.04 × 2.3","unit":"m","source":"Malla triangulada del elemento en ejes locales del edificio","status":"derivado"},{"label":"Cota mínima absoluta de la malla","value":286.25,"unit":"m","source":"Malla de proyecto y origen altimétrico 285 m","status":"derivado"},{"label":"Cota máxima absoluta de la malla","value":288.55,"unit":"m","source":"Malla de proyecto y origen altimétrico 285 m","status":"derivado"},{"label":"Volumen geométrico bruto","value":0.138,"unit":"m³","source":"Malla cerrada del elemento","status":"derivado"},{"label":"Espesor utilizado para representación","value":0.04,"unit":"m","source":"Hipótesis de visualización, no dimensión de fabricación","status":"provisional"}],"notes":["Las dimensiones documentadas proceden de anotaciones o cuadros; la caja y el volumen se calculan a partir de la malla.","El volumen es exclusivamente geométrico y bruto; no representa una medición neta de material ni una cantidad de compra."]} | {"documentId":"ARQ-SB-20260710","title":"Planos de arquitectura de la sala de bombas contra incendios","date":"2026-07-10","sheet":"Arquitectura A101 / p. 3; Carpinterías A109 / p. 11, A110 / p. 12"} | ["Elemento representado por un sólido cerrado único; perfiles de marco y hoja sin detalle de fabricación.","Registro de líneas del PDF general con envolvente de 10,2 × 8,2 m. Estimación de trabajo de implantación de ±0,15 m, pendiente de CAD nativo; no constituye una precisión topográfica garantizada."] | {"horizontalStatus":"derivado","verticalStatus":"provisional","baseElevationM":286.25,"note":"Registro de líneas del PDF general con envolvente de 10,2 × 8,2 m. Estimación de trabajo de implantación de ±0,15 m, pendiente de CAD nativo; no constituye una precisión topográfica garantizada."} | {"Pset_DoorCommon":{"IsExternal":{"value":true,"source":"ARQ-SB-20260710 · A101, A103 y alzados; elemento de la envolvente exterior identificada en planta","status":"known"}}} | {"boundingBoxM":{"min":[16.547658,33.586335,1.25],"max":[18.039127,33.830268,3.55]},"extentsM":[1.491469,0.243933,2.3],"meshSurfaceM2":7.203997,"meshVolumeM3":0.137999,"closedSolid":true,"basis":"Geometría triangulada releída del IFC; envolventes y magnitudes no contractuales."} | {"material":true,"document":true,"quantities":true,"containerGuid":"0Wh59pm9LO_einrwiq6Es1","containerName":"Planta baja"} | {"profileId":"painted_steel","name":"Acero lacado · gris medio","materialName":"Acero lacado","physicalMaterialStatus":"known","physicalMaterialSource":"ARQ-SB-20260710 · A109 / p. 11","appearanceStatus":"criterio_visual","appearanceBasis":"Interpretación visual del material documental; el acabado, tono y parámetros PBR no son una especificación contractual.","note":"La apariencia gráfica no modifica ni confirma la especificación física del material."} | {"elementId":"pump_house_0041","ifcGuid":"0siXwyCG9PyQGPJRpPO_36","ifcClass":"IfcDoor","buildingId":"pump_house","buildingName":"Sala de bombas contra incendios","sourceDocumentId":"ARQ-SB-20260710","sourceRepresentationKind":"documentary_mesh"} | {"profileId":"painted_steel","name":"Acero lacado · gris medio","status":"criterio_visual","basis":"Interpretación visual del material documental; el acabado, tono y parámetros PBR no son una especificación contractual.","physicalMaterialUnchanged":true} | ARQ-SB-20260710 · Arquitectura A101 / p. 3; Carpinterías A109 / p. 11, A110 / p. 12 | Puerta de dos hojas | 1.5 | Registro de líneas del PDF general con envolvente de 10,2 × 8,2 m. Estimación de trabajo de implantación de ±0,15 m, pendiente de CAD nativo; no constituye una precisión topográfica garantizada. | ARQ-SB-20260710 · A109 / p. 11 | Acero lacado · gris medio | painted_steel | [0.521569,0.584314,0.603922] | 0.4 | 0.25
Edificio de oficinas · puerta WM1523_A | Planos de arquitectura del edificio de oficinas; Planos de arquitectura del edificio de oficinas | Madera DM lacada | 1.5 × 0.04 × 2.3 | 285.95 | 288.25 | 0.138 | office_0233 | 0.243933 | 1.49147 | 2.3 | 7.204 | 0.137999 | office | Edificio de oficinas | {"name":"Madera DM lacada","source":"ARQ-OF-20260710 · A108 / p. 10","status":"known"} | {"documented":[{"label":"Anchura del hueco","value":1.5,"unit":"m","source":"ARQ-OF-20260710 · Arquitectura A101 / p. 3; Carpinterías A108 / p. 10, A109 / p. 11","status":"documentado"},{"label":"Altura del hueco","value":2.3,"unit":"m","source":"ARQ-OF-20260710 · Arquitectura A101 / p. 3; Carpinterías A108 / p. 10, A109 / p. 11","status":"documentado"},{"label":"Altura de antepecho","value":0,"unit":"m","source":"ARQ-OF-20260710 · Arquitectura A101 / p. 3; Carpinterías A108 / p. 10, A109 / p. 11","status":"documentado"}],"geometry":[{"label":"Dimensiones de la caja local del elemento (X, Y, Z)","value":"1.5 × 0.04 × 2.3","unit":"m","source":"Malla triangulada del elemento en ejes locales del edificio","status":"derivado"},{"label":"Cota mínima absoluta de la malla","value":285.95,"unit":"m","source":"Malla de proyecto y origen altimétrico 285 m","status":"derivado"},{"label":"Cota máxima absoluta de la malla","value":288.25,"unit":"m","source":"Malla de proyecto y origen altimétrico 285 m","status":"derivado"},{"label":"Volumen geométrico bruto","value":0.138,"unit":"m³","source":"Malla cerrada del elemento","status":"derivado"},{"label":"Espesor utilizado para representación","value":0.04,"unit":"m","source":"Hipótesis de visualización, no dimensión de fabricación","status":"provisional"}],"notes":["Las dimensiones documentadas proceden de anotaciones o cuadros; la caja y el volumen se calculan a partir de la malla.","El volumen es exclusivamente geométrico y bruto; no representa una medición neta de material ni una cantidad de compra."]} | {"documentId":"ARQ-OF-20260710","title":"Planos de arquitectura del edificio de oficinas","date":"2026-07-10","sheet":"Arquitectura A101 / p. 3; Carpinterías A108 / p. 10, A109 / p. 11"} | ["Espesor de hoja de 40 mm aproximado para visualización; anchura y altura del hueco según el cuadro de carpinterías.","El plano general de 2026-07-31 mantiene el edificio de oficinas de 200 m², mientras documentación anterior indica su supresión. Se conserva lo dibujado, pendiente de confirmación de la propiedad y del equipo de diseño.","Elemento representado por un sólido cerrado único; perfiles de marco y hoja sin detalle de fabricación.","Registro de líneas del PDF general, envolvente de 20 × 10 m; eje local 1 al norte y acceso del lado A al oeste. Estimación de trabajo de implantación de ±0,15 m, pendiente de CAD; no constituye una precisión topográfica garantizada."] | {"horizontalStatus":"derivado","verticalStatus":"provisional","baseElevationM":285.95,"note":"Registro de líneas del PDF general, envolvente de 20 × 10 m; eje local 1 al norte y acceso del lado A al oeste. Estimación de trabajo de implantación de ±0,15 m, pendiente de CAD; no constituye una precisión topográfica garantizada."} | {"Pset_DoorCommon":{"IsExternal":{"value":true,"source":"ARQ-OF-20260710 · A101, A103 y alzados; elemento de la envolvente exterior identificada en planta","status":"known"}}} | {"boundingBoxM":{"min":[17.28138,90.424781,0.95],"max":[17.525313,91.916251,3.25]},"extentsM":[0.243933,1.49147,2.3],"meshSurfaceM2":7.204002,"meshVolumeM3":0.137999,"closedSolid":true,"basis":"Geometría triangulada releída del IFC; envolventes y magnitudes no contractuales."} | {"material":true,"document":true,"quantities":true,"containerGuid":"3ztlotcerHPueDgxP84R6z","containerName":"Planta baja"} | {"profileId":"lacquered_wood","name":"Puerta lacada","materialName":"Madera DM lacada","physicalMaterialStatus":"known","physicalMaterialSource":"ARQ-OF-20260710 · A108 / p. 10","appearanceStatus":"criterio_visual","appearanceBasis":"Interpretación visual del material documental; el acabado, tono y parámetros PBR no son una especificación contractual.","note":"La apariencia gráfica no modifica ni confirma la especificación física del material."} | {"elementId":"office_0233","ifcGuid":"1fer_wIG5NdhFSYGWc_1q1","ifcClass":"IfcDoor","buildingId":"office","buildingName":"Edificio de oficinas","sourceDocumentId":"ARQ-OF-20260710","sourceRepresentationKind":"documentary_mesh"} | {"profileId":"lacquered_wood","name":"Puerta lacada","status":"criterio_visual","basis":"Interpretación visual del material documental; el acabado, tono y parámetros PBR no son una especificación contractual.","physicalMaterialUnchanged":true} | ARQ-OF-20260710 · Arquitectura A101 / p. 3; Carpinterías A108 / p. 10, A109 / p. 11 | Puerta de dos hojas | 1.5 | Registro de líneas del PDF general, envolvente de 20 × 10 m; eje local 1 al norte y acceso del lado A al oeste. Estimación de trabajo de implantación de ±0,15 m, pendiente de CAD; no constituye una precisión topográfica garantizada. | ARQ-OF-20260710 · A108 / p. 10 | Puerta lacada | lacquered_wood | [0.835294,0.788235,0.705882] | 0.6 | 0 | JH_Trazabilidad - Comprobación pendiente: Espesor de hoja de 40 mm aproximado para visualización; anchura y altura del hueco según el cuadro de carpinterías.; Discrepancia entre versiones: El plano general de 2026-07-31 mantiene el edificio de oficinas de 200 m², mientras documentación anterior indica su supresión. Se conserva lo dibujado, pendiente de confirmación de la propiedad y del equipo de diseño.
Edificio de oficinas · puerta WM1523_B | Planos de arquitectura del edificio de oficinas; Planos de arquitectura del edificio de oficinas | Madera DM lacada | 1.5 × 0.04 × 2.3 | 285.95 | 288.25 | 0.138 | office_0234 | 0.243933 | 1.49147 | 2.3 | 7.204 | 0.138001 | office | Edificio de oficinas | {"name":"Madera DM lacada","source":"ARQ-OF-20260710 · A108 / p. 10","status":"known"} | {"documented":[{"label":"Anchura del hueco","value":1.5,"unit":"m","source":"ARQ-OF-20260710 · Arquitectura A101 / p. 3; Carpinterías A108 / p. 10, A109 / p. 11","status":"documentado"},{"label":"Altura del hueco","value":2.3,"unit":"m","source":"ARQ-OF-20260710 · Arquitectura A101 / p. 3; Carpinterías A108 / p. 10, A109 / p. 11","status":"documentado"},{"label":"Altura de antepecho","value":0,"unit":"m","source":"ARQ-OF-20260710 · Arquitectura A101 / p. 3; Carpinterías A108 / p. 10, A109 / p. 11","status":"documentado"}],"geometry":[{"label":"Dimensiones de la caja local del elemento (X, Y, Z)","value":"1.5 × 0.04 × 2.3","unit":"m","source":"Malla triangulada del elemento en ejes locales del edificio","status":"derivado"},{"label":"Cota mínima absoluta de la malla","value":285.95,"unit":"m","source":"Malla de proyecto y origen altimétrico 285 m","status":"derivado"},{"label":"Cota máxima absoluta de la malla","value":288.25,"unit":"m","source":"Malla de proyecto y origen altimétrico 285 m","status":"derivado"},{"label":"Volumen geométrico bruto","value":0.138,"unit":"m³","source":"Malla cerrada del elemento","status":"derivado"},{"label":"Espesor utilizado para representación","value":0.04,"unit":"m","source":"Hipótesis de visualización, no dimensión de fabricación","status":"provisional"}],"notes":["Las dimensiones documentadas proceden de anotaciones o cuadros; la caja y el volumen se calculan a partir de la malla.","El volumen es exclusivamente geométrico y bruto; no representa una medición neta de material ni una cantidad de compra."]} | {"documentId":"ARQ-OF-20260710","title":"Planos de arquitectura del edificio de oficinas","date":"2026-07-10","sheet":"Arquitectura A101 / p. 3; Carpinterías A108 / p. 10, A109 / p. 11"} | ["Espesor de hoja de 40 mm aproximado para visualización; anchura y altura del hueco según el cuadro de carpinterías.","El plano general de 2026-07-31 mantiene el edificio de oficinas de 200 m², mientras documentación anterior indica su supresión. Se conserva lo dibujado, pendiente de confirmación de la propiedad y del equipo de diseño.","Elemento representado por un sólido cerrado único; perfiles de marco y hoja sin detalle de fabricación.","Registro de líneas del PDF general, envolvente de 20 × 10 m; eje local 1 al norte y acceso del lado A al oeste. Estimación de trabajo de implantación de ±0,15 m, pendiente de CAD; no constituye una precisión topográfica garantizada."] | {"horizontalStatus":"derivado","verticalStatus":"provisional","baseElevationM":285.95,"note":"Registro de líneas del PDF general, envolvente de 20 × 10 m; eje local 1 al norte y acceso del lado A al oeste. Estimación de trabajo de implantación de ±0,15 m, pendiente de CAD; no constituye una precisión topográfica garantizada."} | {"Pset_DoorCommon":{"IsExternal":{"value":true,"source":"ARQ-OF-20260710 · A101, A103 y alzados; elemento de la envolvente exterior identificada en planta","status":"known"}}} | {"boundingBoxM":{"min":[25.723355,79.876651,0.95],"max":[25.967288,81.368121,3.25]},"extentsM":[0.243933,1.49147,2.3],"meshSurfaceM2":7.204003,"meshVolumeM3":0.138001,"closedSolid":true,"basis":"Geometría triangulada releída del IFC; envolventes y magnitudes no contractuales."} | {"material":true,"document":true,"quantities":true,"containerGuid":"3ztlotcerHPueDgxP84R6z","containerName":"Planta baja"} | {"profileId":"lacquered_wood","name":"Puerta lacada","materialName":"Madera DM lacada","physicalMaterialStatus":"known","physicalMaterialSource":"ARQ-OF-20260710 · A108 / p. 10","appearanceStatus":"criterio_visual","appearanceBasis":"Interpretación visual del material documental; el acabado, tono y parámetros PBR no son una especificación contractual.","note":"La apariencia gráfica no modifica ni confirma la especificación física del material."} | {"elementId":"office_0234","ifcGuid":"1D7XNtdC1IlgygGmfBjrK$","ifcClass":"IfcDoor","buildingId":"office","buildingName":"Edificio de oficinas","sourceDocumentId":"ARQ-OF-20260710","sourceRepresentationKind":"documentary_mesh"} | {"profileId":"lacquered_wood","name":"Puerta lacada","status":"criterio_visual","basis":"Interpretación visual del material documental; el acabado, tono y parámetros PBR no son una especificación contractual.","physicalMaterialUnchanged":true} | ARQ-OF-20260710 · Arquitectura A101 / p. 3; Carpinterías A108 / p. 10, A109 / p. 11 | Puerta de dos hojas | 1.5 | Registro de líneas del PDF general, envolvente de 20 × 10 m; eje local 1 al norte y acceso del lado A al oeste. Estimación de trabajo de implantación de ±0,15 m, pendiente de CAD; no constituye una precisión topográfica garantizada. | ARQ-OF-20260710 · A108 / p. 10 | Puerta lacada | lacquered_wood | [0.835294,0.788235,0.705882] | 0.6 | 0 | JH_Trazabilidad - Comprobación pendiente: Espesor de hoja de 40 mm aproximado para visualización; anchura y altura del hueco según el cuadro de carpinterías.; Discrepancia entre versiones: El plano general de 2026-07-31 mantiene el edificio de oficinas de 200 m², mientras documentación anterior indica su supresión. Se conserva lo dibujado, pendiente de confirmación de la propiedad y del equipo de diseño.

# IfcElectricAppliance: Marcador de equipo en planta, Calentador eléctrico · envolvente exterior documentada
In: Parcela industrial Jinhong
Description: Equipo industrial; PredefinedType: USERDEFINED; Document: Plano del fabricante: cargas de equipos; Plano del fabricante: implantación de equipos · referencia E7; Cimentaciones de equipos y pedestales del fabricante · revisión recibida 04/09/2026; Group: Equipos; Zona de separación de aire; BIM · Equipos
Pset_BuildingElementProxyCommon - Reference: HEATER-PLAN
JH_DimensionesDelModelo - Extensión de la malla en X: 0.749918 m; Extensión de la malla en Y: 0.749918 m; Extensión de la malla en Z: 5.6 m; Cota inferior de visualización: 286.2 m; Cota superior de visualización: 291.8 m
JH_MagnitudesGeometricas - ExtensionX: 0.749918 m; ExtensionY: 0.749918 m; ExtensionZ: 5.6 m; SuperficieDeLaMalla: 14.0739 m2; VolumenGeometrico: 2.47178 m3
JH_CoordinacionCimentaciones - ElementosDeCimentacion: ["found_0904_c3bd5e0d38836a","found_0904_a16d8875227a01","found_0904_bc40ce234e571f"]; Relacion: Correspondencia documental; no verifica anclajes ni cotas de montaje.
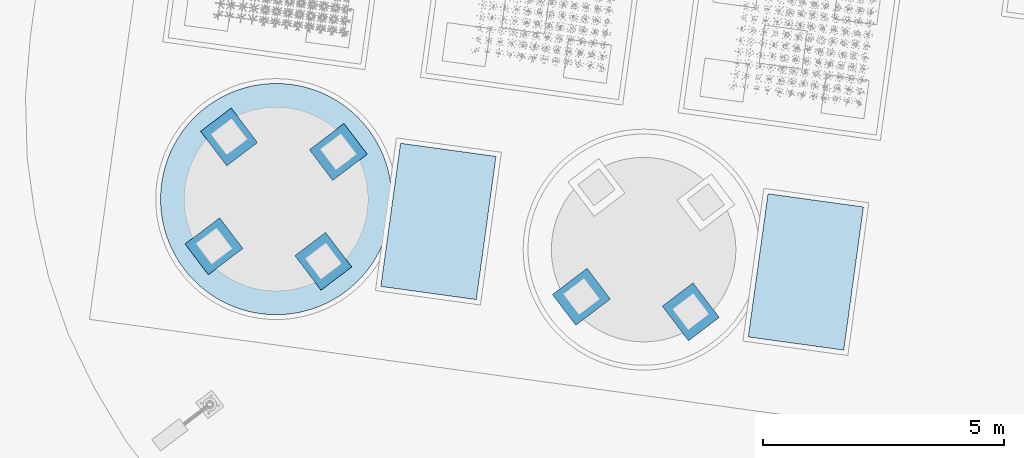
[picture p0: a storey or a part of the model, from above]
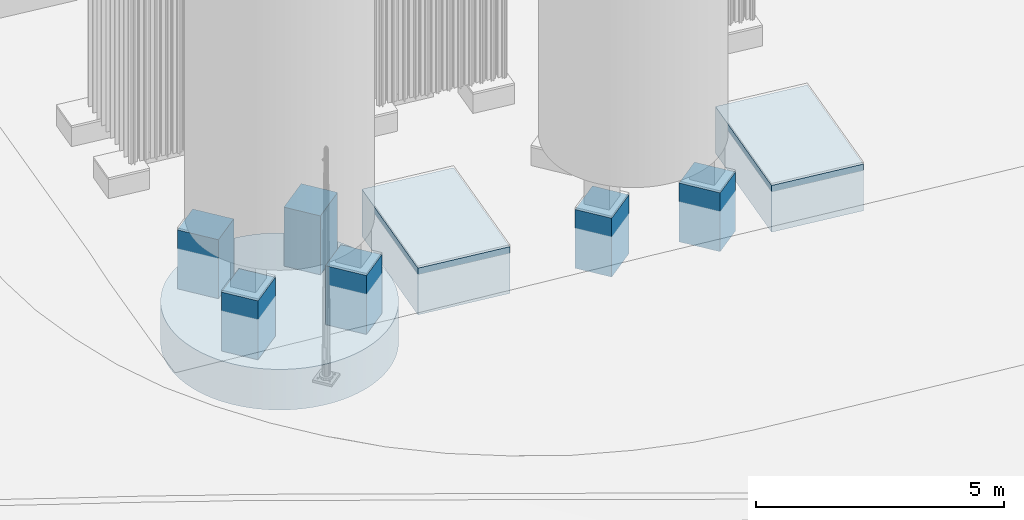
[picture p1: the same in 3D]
Properties of the parts of a building model (IFC4), part 62 of 134

# IfcElectricAppliance: Marcador de equipo en planta, Calentador eléctrico · envolvente exterior documentada
JH_InformacionBIM - buildingId: process_plant; buildingName: Planta de proceso; level: Apoyo relativo +0.100 m; cero absoluto provisional; category: Equipo industrial; ifcClass: IfcElectricAppliance; representationKind: equipment; material: {"name":"No especificado","source":"Los contornos revisados no especifican el material del equipo.","status":"unknown"}; dimensions: {"documented":[{"label":"Diámetro exterior","value":0.749931,"unit":"m","source":"EQ-IMPLANTACION-20260430 · círculo 9C254","status":"derivado"},{"label":"Altura total acotada","value":5.6,"unit":"m","source":"EQ-CARGAS-20260825 · texto de altura 26EF","status":"documentado"},{"label":"Cota relativa de la superficie de apoyo","value":0.1,"unit":"m","source":"LHD2609-JG00100-20260904 · sección 3 / 3-3 · 28D00, 28D41","status":"documentado"}],"geometry":[{"label":"Extensión de la malla en X","value":0.7499184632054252,"unit":"m","source":"Geometría releída del IFC; datum absoluto de proceso provisional","status":"derivado"},{"label":"Extensión de la malla en Y","value":0.7499184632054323,"unit":"m","source":"Geometría releída del IFC; datum absoluto de proceso provisional","status":"derivado"},{"label":"Extensión de la malla en Z","value":5.6,"unit":"m","source":"Geometría releída del IFC; datum absoluto de proceso provisional","status":"derivado"},{"label":"Cota inferior de visualización","value":286.20000000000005,"unit":"m","source":"Geometría releída del IFC; datum absoluto de proceso provisional","status":"derivado"},{"label":"Cota superior de visualización","value":291.8,"unit":"m","source":"Geometría releída del IFC; datum absoluto de proceso provisional","status":"derivado"}],"notes":["Geometría exterior de referencia; los volúmenes no representan cantidades de material, compra o fabricación."]}; source: {"documentId":"EQ-IMPLANTACION-20260430","title":"Plano del fabricante: implantación de equipos · referencia E7","sheet":"Espacio modelo; referencia E7 en el nombre del archivo","date":"2026-04-30"}; status: provisional; positioning: {"Estado de la planta":"Derivado del CAD y del giro de implantación","Nivel relativo del apoyo (m)":0.1,"Estado del nivel relativo":"Documentado en el plano de cimentaciones","Cero absoluto de visualización (m)":286.1,"Estado del cero absoluto":"Provisional","Cota del apoyo de visualización (m)":286.20000000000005,"Desplazamiento aplicado a la malla (m)":0.10000000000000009,"Criterio":"Nivel de apoyo relativo documentado. Se adopta el cero de proceso a 286,10 m solo para visualización; la equivalencia absoluta no está confirmada. No se añade un espesor de montaje sin cota del fabricante."}; issues: ["La altura de 5,60 m está acotada en el plano de cargas; el diámetro exterior se recupera de la circunferencia CAD 9C254.","El cilindro representa la envolvente del equipo; no se conocen los espesores, fondos, distribución de boquillas ni geometría de soportes.","La implantación vertical requiere confirmar la superficie real de montaje.","Cara superior de grout HA-35 de 50 mm a +0,100; hormigón a +0,050.","El cero absoluto de la revisión no está definido; 286,10 m sigue siendo una hipótesis de coordinación.","Se alinea el punto inferior del conjunto del equipo, incluidos los pies ya representados, con la superficie de apoyo terminada; no se añade un espesor de calzos, placa o grout del fabricante no documentado."]; detailGeometry: {"source":{"documentId":"EQ-IMPLANTACION-20260430","title":"Plano del fabricante: implantación de equipos · referencia E7","sheet":"Espacio modelo; referencia E7 en el nombre del archivo","date":"2026-04-30"},"cadSource":"equipment_layout.dxf","conversion":"ODA","sourceInsertHandle":"8DD29","limitations":["La altura de 5,60 m está acotada en el plano de cargas; el diámetro exterior se recupera de la circunferencia CAD 9C254.","El cilindro representa la envolvente del equipo; no se conocen los espesores, fondos, distribución de boquillas ni geometría de soportes.","La implantación vertical requiere confirmar la superficie real de montaje."],"secondarySource":{"documentId":"EQ-CARGAS-20260825","title":"Plano del fabricante: cargas de equipos","sheet":"Espacio modelo; número de plano no identificado","date":"2026-08-25"},"shape":"Envolvente cilíndrica vertical de referencia","heightSourceHandle":"26EF"}; geometryMetrics: {"boundingBoxM":{"min":[53.336308,56.151683,1.2],"max":[54.086226,56.901601,6.8]},"extentsM":[0.749918,0.749918,5.6],"meshSurfaceM2":14.073896,"meshVolumeM3":2.471782,"closedSolid":true,"basis":"Magnitudes de las mallas representadas, no cantidades certificadas de obra, compra o fabricación. Las partes pueden compartir superficies; no se suman como un despiece de materiales."}; installationSource: {"documentId":"LHD2609-JG00100-20260904","title":"Cimentaciones y pedestales de equipos · revisión recibida 04/09/2026","date":"2026-09-04","sheet":"3 / 3-3","sourceHandles":["28D00","28D41"]}; foundationIds: ["found_0904_c3bd5e0d38836a","found_0904_a16d8875227a01","found_0904_bc40ce234e571f"]; visualLayer: {"id":"equipment","name":"Equipos"}; materialAppearance: {"profileId":"equipment_silver","name":"Intercambiador · metal gris provisional","materialName":"No especificado","physicalMaterialStatus":"unknown","physicalMaterialSource":"Los contornos revisados no especifican el material del equipo.","appearanceStatus":"provisional","appearanceBasis":"Referencia visual de fotografías públicas de Jinhong Gas / fabricante. Apariencia provisional para coordinación; fotografías oficiales pueden orientar el color, pero no acreditan el material, el acabado ni el equipo concreto.","note":"La apariencia gráfica no modifica ni confirma la especificación física del material."}; componentSeparation: {"status":"envolvente_del_equipo_sin_interiores","note":"La malla representa el equipo completo o su envolvente. No existe una carcasa separada de los componentes internos."}; visualizationIdentity: {"elementId":"HEATER-PLAN","ifcGuid":"164GHZVovJxOzVnuYctSm4","ifcClass":"IfcElectricAppliance","buildingId":"process_plant","buildingName":"Planta de proceso","sourceDocumentId":"EQ-IMPLANTACION-20260430","sourceRepresentationKind":"equipment"}; classification: {"layerId":"equipment","layerName":"Equipos","role":"Equipo industrial","basis":"Clasificación por función del elemento; no modifica las especificaciones documentales."}; layerId: equipment; appearance: {"profileId":"equipment_silver","name":"Intercambiador · metal gris provisional","status":"provisional","basis":"Referencia visual de fotografías públicas de Jinhong Gas / fabricante. Apariencia provisional para coordinación; fotografías oficiales pueden orientar el color, pero no acreditan el material, el acabado ni el equipo concreto.","physicalMaterialUnchanged":true}
JH_Trazabilidad - Identificador del objeto: HEATER-PLAN; Disciplina: Equipos; Clase IFC: IfcElectricAppliance; Material: No especificado; Estado de la información: provisional; Aplicabilidad a mediciones: Geometría exterior de referencia; los volúmenes no representan cantidades de material, compra o fabricación.; Documento de origen: Plano del fabricante: implantación de equipos · referencia E7; Convención de coordenadas: Metros en la plataforma local del fabricante; transformación de implantación aplicada durante la integración.; Grado de definición: La altura de 5,60 m está acotada en el plano de cargas; el diámetro exterior se recupera de la circunferencia CAD 9C254.; El cilindro representa la envolvente del equipo; no se conocen los espesores, fondos, distribución de boquillas ni geometría de soportes.; La implantación vertical requiere confirmar la superficie real de montaje.; Identificadores CAD del contorno (handles): 9C254, 26EF; Nivel relativo de apoyo documentado (m): 0.1; Fuente del nivel de apoyo: {"documentId":"LHD2609-JG00100-20260904","title":"Cimentaciones y pedestales de equipos · revisión recibida 04/09/2026","date":"2026-09-04","sheet":"3 / 3-3","sourceHandles":["28D00","28D41"]}; Criterio de instalación: Nivel de apoyo relativo documentado. Se adopta el cero de proceso a 286,10 m solo para visualización; la equivalencia absoluta no está confirmada. No se añade un espesor de montaje sin cota del fabricante.; Fase del modelo: Revisión de la zona de separación de aire · septiembre de 2026; Capa BIM: Equipos; Acabado de visualización: Intercambiador · metal gris provisional; Estado del acabado: provisional; Identificador: HEATER-PLAN; Categoria: Equipo industrial; ClaseIFC: IfcElectricAppliance; EstadoDeInformacion: provisional; DocumentoFuente: {"documentId":"EQ-IMPLANTACION-20260430","title":"Plano del fabricante: implantación de equipos · referencia E7","sheet":"Espacio modelo; referencia E7 en el nombre del archivo","date":"2026-04-30"}; IncidenciasPendientes: ["La altura de 5,60 m está acotada en el plano de cargas; el diámetro exterior se recupera de la circunferencia CAD 9C254.","El cilindro representa la envolvente del equipo; no se conocen los espesores, fondos, distribución de boquillas ni geometría de soportes.","La implantación vertical requiere confirmar la superficie real de montaje.","Cara superior de grout HA-35 de 50 mm a +0,100; hormigón a +0,050.","El cero absoluto de la revisión no está definido; 286,10 m sigue siendo una hipótesis de coordinación.","Se alinea el punto inferior del conjunto del equipo, incluidos los pies ya representados, con la superficie de apoyo terminada; no se añade un espesor de calzos, placa o grout del fabricante no documentado."]; UsoDeLasMagnitudes: Geometría de coordinación. Los volúmenes de referencia y subcomponentes no son cantidades de material ni componentes de fabricación certificados.
JH_CriterioDePosicion - PosicionYEstado: {"Estado de la planta":"Derivado del CAD y del giro de implantación","Nivel relativo del apoyo (m)":0.1,"Estado del nivel relativo":"Documentado en el plano de cimentaciones","Cero absoluto de visualización (m)":286.1,"Estado del cero absoluto":"Provisional","Cota del apoyo de visualización (m)":286.20000000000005,"Desplazamiento aplicado a la malla (m)":0.10000000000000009,"Criterio":"Nivel de apoyo relativo documentado. Se adopta el cero de proceso a 286,10 m solo para visualización; la equivalencia absoluta no está confirmada. No se añade un espesor de montaje sin cota del fabricante."}
JH_EvidenciaDeMaterial - name: No especificado; source: Los contornos revisados no especifican el material del equipo.; status: unknown
JH_DimensionesDocumentadas - Diámetro exterior: 0.749931 m; Altura total acotada: 5.6 m; Cota relativa de la superficie de apoyo: 0.1 m
JH_DetalleGeometrico - source: {"documentId":"EQ-IMPLANTACION-20260430","title":"Plano del fabricante: implantación de equipos · referencia E7","sheet":"Espacio modelo; referencia E7 en el nombre del archivo","date":"2026-04-30"}; cadSource: equipment_layout.dxf; conversion: ODA; sourceInsertHandle: 8DD29; limitations: ["La altura de 5,60 m está acotada en el plano de cargas; el diámetro exterior se recupera de la circunferencia CAD 9C254.","El cilindro representa la envolvente del equipo; no se conocen los espesores, fondos, distribución de boquillas ni geometría de soportes.","La implantación vertical requiere confirmar la superficie real de montaje."]; secondarySource: {"documentId":"EQ-CARGAS-20260825","title":"Plano del fabricante: cargas de equipos","sheet":"Espacio modelo; número de plano no identificado","date":"2026-08-25"}; shape: Envolvente cilíndrica vertical de referencia; heightSourceHandle: 26EF
JH_CapaBIM - IdentificadorCapa: equipment; NombreCapa: Equipos; Funcion: Equipo industrial; VisibilidadInicial: yes
JH_AcabadoVisual - Perfil: equipment_silver; Acabado: Intercambiador · metal gris provisional; ColorRGB: [0.68,0.72,0.75]; Rugosidad: 0.38; Metallicidad: 0.7; Estado: provisional; Referencia: Referencia visual de fotografías públicas de Jinhong Gas / fabricante. Apariencia provisional para coordinación; fotografías oficiales pueden orientar el color, pero no acreditan el material, el acabado ni el equipo concreto.; Nota: La apariencia no certifica el material físico ni el acabado de fabricación.

# IfcElementAssembly: Pórtico metálico de tuberías · 1
In: Parcela industrial Jinhong
Description: Esquema provisional de coordinación autorizado por el cliente. Tuberías, soportes, alumbrado e hidrantes con dimensiones y posiciones orientativas; no para construcción ni cómputo de cantidades.; PredefinedType: USERDEFINED; Document: Indicación del cliente y croquis sobre el visor · 08/09/2026; Group: BIM · Galería de nitrógeno · esquema
JH_InformacionBIM - buildingId: site; buildingName: Urbanización y parcela; level: Exterior · esquema de servicios; category: Pórtico metálico de tuberías · 1; ifcClass: IfcElementAssembly; status: provisional; source: {"documentId":"JH-USER-N2-20260908","title":"Indicación del cliente y croquis sobre el visor · 08/09/2026","date":"2026-09-08","sheet":"Recorrido orientativo señalado en rojo","note":"Diámetros aproximados de 0,50 y 0,20 m solicitados por el cliente. No es un plano de ingeniería."}; material: {"name":"Bastidor metálico · gris","status":"provisional","source":"Material, espesor, aislamiento y protección pendientes de ingeniería."}; dimensions: {"documented":[],"assumed":[{"label":"Separación transversal de pilares","value":2.2,"unit":"m"},{"label":"Perfil gráfico de pilares y travesaños","value":0.16,"unit":"m"},{"label":"Placa / dado orientativo de apoyo","value":0.4,"unit":"m"},{"label":"Criterio","value":"Pórticos laterales y travesaños que envuelven las dos tuberías; sin cálculo estructural","unit":""}],"geometry":[{"label":"Extensión representada X","value":2.630252,"unit":"m"},{"label":"Extensión representada Y","value":0.750402,"unit":"m"},{"label":"Extensión representada Z","value":6.98,"unit":"m"}]}; appearance: {"profileId":"n2_rack_steel","name":"Bastidor metálico · gris","status":"criterio_visual","basis":"Color y acabado orientativos para distinguir el esquema solicitado; material sin especificación confirmada."}; classification: {"layerId":"pipe_gallery","layerName":"Galería de nitrógeno · esquema","function":"Pórtico metálico de tuberías · 1"}; visualLayer: {"id":"pipe_gallery","name":"Galería de nitrógeno · esquema","defaultVisible":true}; representationKind: esquema_provisional_no_constructivo; conceptual: {"enabled":true,"basis":"Esquema provisional solicitado por el cliente. Trazado, altura, profundidad, soportes, material y conexiones pendientes de plano; no para construcción ni cómputo de cantidades.","pending":["Plano de ruta y servidumbre exterior","Alturas, profundidad y recubrimiento","Clase de tubería, presión, espesor, aislamiento y uniones","Cálculo de soportes, dilatación y conexiones reales"]}; positioning: {"Trazado":"Desde el entorno de la caja fría hacia el borde sur indicado en el croquis; entrada al subsuelo dentro de la parcela.","Entrada al subsuelo":"Eje aproximado a 1,19 m del lindero; dos tuberías desplazadas ±0,45 m lateralmente.","Terreno exterior":"Nivel provisional prolongado desde la entrada al subsuelo; no se aporta levantamiento exterior ni se amplía la parcela."}; quantityEligible: no; issues: ["Esquema provisional solicitado por el cliente. Trazado, altura, profundidad, soportes, material y conexiones pendientes de plano; no para construcción ni cómputo de cantidades.","La posición de la salida exterior y el terreno de contexto son orientativos, sin confirmar propiedad, permisos ni destino de conexión."]; rackStationM: 6; rackBeamCenterZM: 6.75; rackUpperBeamCenterZM: 8; isOutletSupport: no; geometryMetrics: {"boundingBoxM":{"min":[56.867651,34.180714,1.1],"max":[59.497903,34.931116,8.08]},"extentsM":[2.630252,0.750402,6.98],"meshSurfaceM2":14.156001,"meshVolumeM3":0.569612,"closedSolid":true,"basis":"Esquema provisional de coordinación autorizado por el cliente. Tuberías, soportes, alumbrado e hidrantes con dimensiones y posiciones orientativas; no para construcción ni cómputo de cantidades."}
JH_Trazabilidad - Origen: Croquis e indicación del cliente · 08/09/2026; Estado: Provisional · no para construcción; Capa BIM: Galería de nitrógeno · esquema; Mediciones de obra: Excluido; Identificador: N2-RACK-FRAME-01; Categoria: Pórtico metálico de tuberías · 1; ClaseIFC: IfcElementAssembly; EstadoDeInformacion: provisional; DocumentoFuente: {"documentId":"JH-USER-N2-20260908","title":"Indicación del cliente y croquis sobre el visor · 08/09/2026","date":"2026-09-08","sheet":"Recorrido orientativo señalado en rojo","note":"Diámetros aproximados de 0,50 y 0,20 m solicitados por el cliente. No es un plano de ingeniería."}; IncidenciasPendientes: ["Esquema provisional solicitado por el cliente. Trazado, altura, profundidad, soportes, material y conexiones pendientes de plano; no para construcción ni cómputo de cantidades.","La posición de la salida exterior y el terreno de contexto son orientativos, sin confirmar propiedad, permisos ni destino de conexión."]; UsoDeLasMagnitudes: Esquema provisional de coordinación autorizado por el cliente. Tuberías, soportes, alumbrado e hidrantes con dimensiones y posiciones orientativas; no para construcción ni cómputo de cantidades.
JH_CriterioDePosicion - PosicionYEstado: {"Trazado":"Desde el entorno de la caja fría hacia el borde sur indicado en el croquis; entrada al subsuelo dentro de la parcela.","Entrada al subsuelo":"Eje aproximado a 1,19 m del lindero; dos tuberías desplazadas ±0,45 m lateralmente.","Terreno exterior":"Nivel provisional prolongado desde la entrada al subsuelo; no se aporta levantamiento exterior ni se amplía la parcela."}
JH_EvidenciaDeMaterial - name: Bastidor metálico · gris; status: provisional; source: Material, espesor, aislamiento y protección pendientes de ingeniería.
JH_CapaBIM - IdentificadorCapa: pipe_gallery; NombreCapa: Galería de nitrógeno · esquema; Funcion: Pórtico metálico de tuberías · 1; VisibilidadInicial: yes
JH_EsquemaProvisional - Estado: No para construcción; Origen: {"documentId":"JH-USER-N2-20260908","title":"Indicación del cliente y croquis sobre el visor · 08/09/2026","date":"2026-09-08","sheet":"Recorrido orientativo señalado en rojo","note":"Diámetros aproximados de 0,50 y 0,20 m solicitados por el cliente. No es un plano de ingeniería."}; DimensionesSupuestas: [{"label":"Separación transversal de pilares","value":2.2,"unit":"m"},{"label":"Perfil gráfico de pilares y travesaños","value":0.16,"unit":"m"},{"label":"Placa / dado orientativo de apoyo","value":0.4,"unit":"m"},{"label":"Criterio","value":"Pórticos laterales y travesaños que envuelven las dos tuberías; sin cálculo estructural","unit":""}]; Posicion: {"Trazado":"Desde el entorno de la caja fría hacia el borde sur indicado en el croquis; entrada al subsuelo dentro de la parcela.","Entrada al subsuelo":"Eje aproximado a 1,19 m del lindero; dos tuberías desplazadas ±0,45 m lateralmente.","Terreno exterior":"Nivel provisional prolongado desde la entrada al subsuelo; no se aporta levantamiento exterior ni se amplía la parcela."}; IncluirEnMediciones: no; Criterio: {"enabled":true,"basis":"Esquema provisional solicitado por el cliente. Trazado, altura, profundidad, soportes, material y conexiones pendientes de plano; no para construcción ni cómputo de cantidades.","pending":["Plano de ruta y servidumbre exterior","Alturas, profundidad y recubrimiento","Clase de tubería, presión, espesor, aislamiento y uniones","Cálculo de soportes, dilatación y conexiones reales"]}

# IfcElementAssembly: Pórtico metálico de tuberías · 2
In: Parcela industrial Jinhong
Description: Esquema provisional de coordinación autorizado por el cliente. Tuberías, soportes, alumbrado e hidrantes con dimensiones y posiciones orientativas; no para construcción ni cómputo de cantidades.; PredefinedType: USERDEFINED; Document: Indicación del cliente y croquis sobre el visor · 08/09/2026; Group: BIM · Galería de nitrógeno · esquema
JH_InformacionBIM - buildingId: site; buildingName: Urbanización y parcela; level: Exterior · esquema de servicios; category: Pórtico metálico de tuberías · 2; ifcClass: IfcElementAssembly; status: provisional; source: {"documentId":"JH-USER-N2-20260908","title":"Indicación del cliente y croquis sobre el visor · 08/09/2026","date":"2026-09-08","sheet":"Recorrido orientativo señalado en rojo","note":"Diámetros aproximados de 0,50 y 0,20 m solicitados por el cliente. No es un plano de ingeniería."}; material: {"name":"Bastidor metálico · gris","status":"provisional","source":"Material, espesor, aislamiento y protección pendientes de ingeniería."}; dimensions: {"documented":[],"assumed":[{"label":"Separación transversal de pilares","value":2.2,"unit":"m"},{"label":"Perfil gráfico de pilares y travesaños","value":0.16,"unit":"m"},{"label":"Placa / dado orientativo de apoyo","value":0.4,"unit":"m"},{"label":"Criterio","value":"Pórticos laterales y travesaños que envuelven las dos tuberías; sin cálculo estructural","unit":""}],"geometry":[{"label":"Extensión representada X","value":2.630251,"unit":"m"},{"label":"Extensión representada Y","value":0.750402,"unit":"m"},{"label":"Extensión representada Z","value":6.98,"unit":"m"}]}; appearance: {"profileId":"n2_rack_steel","name":"Bastidor metálico · gris","status":"criterio_visual","basis":"Color y acabado orientativos para distinguir el esquema solicitado; material sin especificación confirmada."}; classification: {"layerId":"pipe_gallery","layerName":"Galería de nitrógeno · esquema","function":"Pórtico metálico de tuberías · 2"}; visualLayer: {"id":"pipe_gallery","name":"Galería de nitrógeno · esquema","defaultVisible":true}; representationKind: esquema_provisional_no_constructivo; conceptual: {"enabled":true,"basis":"Esquema provisional solicitado por el cliente. Trazado, altura, profundidad, soportes, material y conexiones pendientes de plano; no para construcción ni cómputo de cantidades.","pending":["Plano de ruta y servidumbre exterior","Alturas, profundidad y recubrimiento","Clase de tubería, presión, espesor, aislamiento y uniones","Cálculo de soportes, dilatación y conexiones reales"]}; positioning: {"Trazado":"Desde el entorno de la caja fría hacia el borde sur indicado en el croquis; entrada al subsuelo dentro de la parcela.","Entrada al subsuelo":"Eje aproximado a 1,19 m del lindero; dos tuberías desplazadas ±0,45 m lateralmente.","Terreno exterior":"Nivel provisional prolongado desde la entrada al subsuelo; no se aporta levantamiento exterior ni se amplía la parcela."}; quantityEligible: no; issues: ["Esquema provisional solicitado por el cliente. Trazado, altura, profundidad, soportes, material y conexiones pendientes de plano; no para construcción ni cómputo de cantidades.","La posición de la salida exterior y el terreno de contexto son orientativos, sin confirmar propiedad, permisos ni destino de conexión."]; rackStationM: 12; rackBeamCenterZM: 6.75; rackUpperBeamCenterZM: 8; isOutletSupport: no; geometryMetrics: {"boundingBoxM":{"min":[56.050428,28.236629,1.1],"max":[58.680679,28.987031,8.08]},"extentsM":[2.630251,0.750402,6.98],"meshSurfaceM2":14.156001,"meshVolumeM3":0.569612,"closedSolid":true,"basis":"Esquema provisional de coordinación autorizado por el cliente. Tuberías, soportes, alumbrado e hidrantes con dimensiones y posiciones orientativas; no para construcción ni cómputo de cantidades."}
JH_Trazabilidad - Origen: Croquis e indicación del cliente · 08/09/2026; Estado: Provisional · no para construcción; Capa BIM: Galería de nitrógeno · esquema; Mediciones de obra: Excluido; Identificador: N2-RACK-FRAME-02; Categoria: Pórtico metálico de tuberías · 2; ClaseIFC: IfcElementAssembly; EstadoDeInformacion: provisional; DocumentoFuente: {"documentId":"JH-USER-N2-20260908","title":"Indicación del cliente y croquis sobre el visor · 08/09/2026","date":"2026-09-08","sheet":"Recorrido orientativo señalado en rojo","note":"Diámetros aproximados de 0,50 y 0,20 m solicitados por el cliente. No es un plano de ingeniería."}; IncidenciasPendientes: ["Esquema provisional solicitado por el cliente. Trazado, altura, profundidad, soportes, material y conexiones pendientes de plano; no para construcción ni cómputo de cantidades.","La posición de la salida exterior y el terreno de contexto son orientativos, sin confirmar propiedad, permisos ni destino de conexión."]; UsoDeLasMagnitudes: Esquema provisional de coordinación autorizado por el cliente. Tuberías, soportes, alumbrado e hidrantes con dimensiones y posiciones orientativas; no para construcción ni cómputo de cantidades.
JH_CriterioDePosicion - PosicionYEstado: {"Trazado":"Desde el entorno de la caja fría hacia el borde sur indicado en el croquis; entrada al subsuelo dentro de la parcela.","Entrada al subsuelo":"Eje aproximado a 1,19 m del lindero; dos tuberías desplazadas ±0,45 m lateralmente.","Terreno exterior":"Nivel provisional prolongado desde la entrada al subsuelo; no se aporta levantamiento exterior ni se amplía la parcela."}
JH_EvidenciaDeMaterial - name: Bastidor metálico · gris; status: provisional; source: Material, espesor, aislamiento y protección pendientes de ingeniería.
JH_CapaBIM - IdentificadorCapa: pipe_gallery; NombreCapa: Galería de nitrógeno · esquema; Funcion: Pórtico metálico de tuberías · 2; VisibilidadInicial: yes
JH_EsquemaProvisional - Estado: No para construcción; Origen: {"documentId":"JH-USER-N2-20260908","title":"Indicación del cliente y croquis sobre el visor · 08/09/2026","date":"2026-09-08","sheet":"Recorrido orientativo señalado en rojo","note":"Diámetros aproximados de 0,50 y 0,20 m solicitados por el cliente. No es un plano de ingeniería."}; DimensionesSupuestas: [{"label":"Separación transversal de pilares","value":2.2,"unit":"m"},{"label":"Perfil gráfico de pilares y travesaños","value":0.16,"unit":"m"},{"label":"Placa / dado orientativo de apoyo","value":0.4,"unit":"m"},{"label":"Criterio","value":"Pórticos laterales y travesaños que envuelven las dos tuberías; sin cálculo estructural","unit":""}]; Posicion: {"Trazado":"Desde el entorno de la caja fría hacia el borde sur indicado en el croquis; entrada al subsuelo dentro de la parcela.","Entrada al subsuelo":"Eje aproximado a 1,19 m del lindero; dos tuberías desplazadas ±0,45 m lateralmente.","Terreno exterior":"Nivel provisional prolongado desde la entrada al subsuelo; no se aporta levantamiento exterior ni se amplía la parcela."}; IncluirEnMediciones: no; Criterio: {"enabled":true,"basis":"Esquema provisional solicitado por el cliente. Trazado, altura, profundidad, soportes, material y conexiones pendientes de plano; no para construcción ni cómputo de cantidades.","pending":["Plano de ruta y servidumbre exterior","Alturas, profundidad y recubrimiento","Clase de tubería, presión, espesor, aislamiento y uniones","Cálculo de soportes, dilatación y conexiones reales"]}

# IfcElementAssembly: Pórtico metálico de tuberías · 3
In: Parcela industrial Jinhong
Description: Esquema provisional de coordinación autorizado por el cliente. Tuberías, soportes, alumbrado e hidrantes con dimensiones y posiciones orientativas; no para construcción ni cómputo de cantidades.; PredefinedType: USERDEFINED; Document: Indicación del cliente y croquis sobre el visor · 08/09/2026; Group: BIM · Galería de nitrógeno · esquema
JH_InformacionBIM - buildingId: site; buildingName: Urbanización y parcela; level: Exterior · esquema de servicios; category: Pórtico metálico de tuberías · 3; ifcClass: IfcElementAssembly; status: provisional; source: {"documentId":"JH-USER-N2-20260908","title":"Indicación del cliente y croquis sobre el visor · 08/09/2026","date":"2026-09-08","sheet":"Recorrido orientativo señalado en rojo","note":"Diámetros aproximados de 0,50 y 0,20 m solicitados por el cliente. No es un plano de ingeniería."}; material: {"name":"Bastidor metálico · gris","status":"provisional","source":"Material, espesor, aislamiento y protección pendientes de ingeniería."}; dimensions: {"documented":[],"assumed":[{"label":"Separación transversal de pilares","value":2.2,"unit":"m"},{"label":"Perfil gráfico de pilares y travesaños","value":0.16,"unit":"m"},{"label":"Placa / dado orientativo de apoyo","value":0.4,"unit":"m"},{"label":"Criterio","value":"Pórticos laterales y travesaños que envuelven las dos tuberías; sin cálculo estructural","unit":""}],"geometry":[{"label":"Extensión representada X","value":2.630252,"unit":"m"},{"label":"Extensión representada Y","value":0.750402,"unit":"m"},{"label":"Extensión representada Z","value":6.678265,"unit":"m"}]}; appearance: {"profileId":"n2_rack_steel","name":"Bastidor metálico · gris","status":"criterio_visual","basis":"Color y acabado orientativos para distinguir el esquema solicitado; material sin especificación confirmada."}; classification: {"layerId":"pipe_gallery","layerName":"Galería de nitrógeno · esquema","function":"Pórtico metálico de tuberías · 3"}; visualLayer: {"id":"pipe_gallery","name":"Galería de nitrógeno · esquema","defaultVisible":true}; representationKind: esquema_provisional_no_constructivo; conceptual: {"enabled":true,"basis":"Esquema provisional solicitado por el cliente. Trazado, altura, profundidad, soportes, material y conexiones pendientes de plano; no para construcción ni cómputo de cantidades.","pending":["Plano de ruta y servidumbre exterior","Alturas, profundidad y recubrimiento","Clase de tubería, presión, espesor, aislamiento y uniones","Cálculo de soportes, dilatación y conexiones reales"]}; positioning: {"Trazado":"Desde el entorno de la caja fría hacia el borde sur indicado en el croquis; entrada al subsuelo dentro de la parcela.","Entrada al subsuelo":"Eje aproximado a 1,19 m del lindero; dos tuberías desplazadas ±0,45 m lateralmente.","Terreno exterior":"Nivel provisional prolongado desde la entrada al subsuelo; no se aporta levantamiento exterior ni se amplía la parcela."}; quantityEligible: no; issues: ["Esquema provisional solicitado por el cliente. Trazado, altura, profundidad, soportes, material y conexiones pendientes de plano; no para construcción ni cómputo de cantidades.","La posición de la salida exterior y el terreno de contexto son orientativos, sin confirmar propiedad, permisos ni destino de conexión."]; rackStationM: 19.3; rackBeamCenterZM: 6.75; rackUpperBeamCenterZM: 8; isOutletSupport: no; geometryMetrics: {"boundingBoxM":{"min":[55.056139,21.004659,1.401735],"max":[57.686391,21.755061,8.08]},"extentsM":[2.630252,0.750402,6.678265],"meshSurfaceM2":13.757773,"meshVolumeM3":0.553683,"closedSolid":true,"basis":"Esquema provisional de coordinación autorizado por el cliente. Tuberías, soportes, alumbrado e hidrantes con dimensiones y posiciones orientativas; no para construcción ni cómputo de cantidades."}
JH_Trazabilidad - Origen: Croquis e indicación del cliente · 08/09/2026; Estado: Provisional · no para construcción; Capa BIM: Galería de nitrógeno · esquema; Mediciones de obra: Excluido; Identificador: N2-RACK-FRAME-03; Categoria: Pórtico metálico de tuberías · 3; ClaseIFC: IfcElementAssembly; EstadoDeInformacion: provisional; DocumentoFuente: {"documentId":"JH-USER-N2-20260908","title":"Indicación del cliente y croquis sobre el visor · 08/09/2026","date":"2026-09-08","sheet":"Recorrido orientativo señalado en rojo","note":"Diámetros aproximados de 0,50 y 0,20 m solicitados por el cliente. No es un plano de ingeniería."}; IncidenciasPendientes: ["Esquema provisional solicitado por el cliente. Trazado, altura, profundidad, soportes, material y conexiones pendientes de plano; no para construcción ni cómputo de cantidades.","La posición de la salida exterior y el terreno de contexto son orientativos, sin confirmar propiedad, permisos ni destino de conexión."]; UsoDeLasMagnitudes: Esquema provisional de coordinación autorizado por el cliente. Tuberías, soportes, alumbrado e hidrantes con dimensiones y posiciones orientativas; no para construcción ni cómputo de cantidades.
JH_CriterioDePosicion - PosicionYEstado: {"Trazado":"Desde el entorno de la caja fría hacia el borde sur indicado en el croquis; entrada al subsuelo dentro de la parcela.","Entrada al subsuelo":"Eje aproximado a 1,19 m del lindero; dos tuberías desplazadas ±0,45 m lateralmente.","Terreno exterior":"Nivel provisional prolongado desde la entrada al subsuelo; no se aporta levantamiento exterior ni se amplía la parcela."}
JH_EvidenciaDeMaterial - name: Bastidor metálico · gris; status: provisional; source: Material, espesor, aislamiento y protección pendientes de ingeniería.
JH_CapaBIM - IdentificadorCapa: pipe_gallery; NombreCapa: Galería de nitrógeno · esquema; Funcion: Pórtico metálico de tuberías · 3; VisibilidadInicial: yes
JH_EsquemaProvisional - Estado: No para construcción; Origen: {"documentId":"JH-USER-N2-20260908","title":"Indicación del cliente y croquis sobre el visor · 08/09/2026","date":"2026-09-08","sheet":"Recorrido orientativo señalado en rojo","note":"Diámetros aproximados de 0,50 y 0,20 m solicitados por el cliente. No es un plano de ingeniería."}; DimensionesSupuestas: [{"label":"Separación transversal de pilares","value":2.2,"unit":"m"},{"label":"Perfil gráfico de pilares y travesaños","value":0.16,"unit":"m"},{"label":"Placa / dado orientativo de apoyo","value":0.4,"unit":"m"},{"label":"Criterio","value":"Pórticos laterales y travesaños que envuelven las dos tuberías; sin cálculo estructural","unit":""}]; Posicion: {"Trazado":"Desde el entorno de la caja fría hacia el borde sur indicado en el croquis; entrada al subsuelo dentro de la parcela.","Entrada al subsuelo":"Eje aproximado a 1,19 m del lindero; dos tuberías desplazadas ±0,45 m lateralmente.","Terreno exterior":"Nivel provisional prolongado desde la entrada al subsuelo; no se aporta levantamiento exterior ni se amplía la parcela."}; IncluirEnMediciones: no; Criterio: {"enabled":true,"basis":"Esquema provisional solicitado por el cliente. Trazado, altura, profundidad, soportes, material y conexiones pendientes de plano; no para construcción ni cómputo de cantidades.","pending":["Plano de ruta y servidumbre exterior","Alturas, profundidad y recubrimiento","Clase de tubería, presión, espesor, aislamiento y uniones","Cálculo de soportes, dilatación y conexiones reales"]}

# IfcElementAssembly: Pórtico metálico de tuberías · 4
In: Parcela industrial Jinhong
Description: Esquema provisional de coordinación autorizado por el cliente. Tuberías, soportes, alumbrado e hidrantes con dimensiones y posiciones orientativas; no para construcción ni cómputo de cantidades.; PredefinedType: USERDEFINED; Document: Indicación del cliente y croquis sobre el visor · 08/09/2026; Group: BIM · Galería de nitrógeno · esquema
JH_InformacionBIM - buildingId: site; buildingName: Urbanización y parcela; level: Exterior · esquema de servicios; category: Pórtico metálico de tuberías · 4; ifcClass: IfcElementAssembly; status: provisional; source: {"documentId":"JH-USER-N2-20260908","title":"Indicación del cliente y croquis sobre el visor · 08/09/2026","date":"2026-09-08","sheet":"Recorrido orientativo señalado en rojo","note":"Diámetros aproximados de 0,50 y 0,20 m solicitados por el cliente. No es un plano de ingeniería."}; material: {"name":"Bastidor metálico · gris","status":"provisional","source":"Material, espesor, aislamiento y protección pendientes de ingeniería."}; dimensions: {"documented":[],"assumed":[{"label":"Separación transversal de pilares","value":2.2,"unit":"m"},{"label":"Perfil gráfico de pilares y travesaños","value":0.16,"unit":"m"},{"label":"Placa / dado orientativo de apoyo","value":0.4,"unit":"m"},{"label":"Criterio","value":"Pórticos laterales y travesaños que envuelven las dos tuberías; sin cálculo estructural","unit":""}],"geometry":[{"label":"Extensión representada X","value":2.630252,"unit":"m"},{"label":"Extensión representada Y","value":0.750402,"unit":"m"},{"label":"Extensión representada Z","value":6.819394,"unit":"m"}]}; appearance: {"profileId":"n2_rack_steel","name":"Bastidor metálico · gris","status":"criterio_visual","basis":"Color y acabado orientativos para distinguir el esquema solicitado; material sin especificación confirmada."}; classification: {"layerId":"pipe_gallery","layerName":"Galería de nitrógeno · esquema","function":"Pórtico metálico de tuberías · 4"}; visualLayer: {"id":"pipe_gallery","name":"Galería de nitrógeno · esquema","defaultVisible":true}; representationKind: esquema_provisional_no_constructivo; conceptual: {"enabled":true,"basis":"Esquema provisional solicitado por el cliente. Trazado, altura, profundidad, soportes, material y conexiones pendientes de plano; no para construcción ni cómputo de cantidades.","pending":["Plano de ruta y servidumbre exterior","Alturas, profundidad y recubrimiento","Clase de tubería, presión, espesor, aislamiento y uniones","Cálculo de soportes, dilatación y conexiones reales"]}; positioning: {"Trazado":"Desde el entorno de la caja fría hacia el borde sur indicado en el croquis; entrada al subsuelo dentro de la parcela.","Entrada al subsuelo":"Eje aproximado a 1,19 m del lindero; dos tuberías desplazadas ±0,45 m lateralmente.","Terreno exterior":"Nivel provisional prolongado desde la entrada al subsuelo; no se aporta levantamiento exterior ni se amplía la parcela."}; quantityEligible: no; issues: ["Esquema provisional solicitado por el cliente. Trazado, altura, profundidad, soportes, material y conexiones pendientes de plano; no para construcción ni cómputo de cantidades.","La posición de la salida exterior y el terreno de contexto son orientativos, sin confirmar propiedad, permisos ni destino de conexión."]; rackStationM: 26.85; rackBeamCenterZM: 6.15; rackUpperBeamCenterZM: 8; isOutletSupport: no; geometryMetrics: {"boundingBoxM":{"min":[54.0278,13.525019,1.260606],"max":[56.658052,14.275421,8.08]},"extentsM":[2.630252,0.750402,6.819394],"meshSurfaceM2":14.175607,"meshVolumeM3":0.578413,"closedSolid":true,"basis":"Esquema provisional de coordinación autorizado por el cliente. Tuberías, soportes, alumbrado e hidrantes con dimensiones y posiciones orientativas; no para construcción ni cómputo de cantidades."}
JH_Trazabilidad - Origen: Croquis e indicación del cliente · 08/09/2026; Estado: Provisional · no para construcción; Capa BIM: Galería de nitrógeno · esquema; Mediciones de obra: Excluido; Identificador: N2-RACK-FRAME-04; Categoria: Pórtico metálico de tuberías · 4; ClaseIFC: IfcElementAssembly; EstadoDeInformacion: provisional; DocumentoFuente: {"documentId":"JH-USER-N2-20260908","title":"Indicación del cliente y croquis sobre el visor · 08/09/2026","date":"2026-09-08","sheet":"Recorrido orientativo señalado en rojo","note":"Diámetros aproximados de 0,50 y 0,20 m solicitados por el cliente. No es un plano de ingeniería."}; IncidenciasPendientes: ["Esquema provisional solicitado por el cliente. Trazado, altura, profundidad, soportes, material y conexiones pendientes de plano; no para construcción ni cómputo de cantidades.","La posición de la salida exterior y el terreno de contexto son orientativos, sin confirmar propiedad, permisos ni destino de conexión."]; UsoDeLasMagnitudes: Esquema provisional de coordinación autorizado por el cliente. Tuberías, soportes, alumbrado e hidrantes con dimensiones y posiciones orientativas; no para construcción ni cómputo de cantidades.
JH_CriterioDePosicion - PosicionYEstado: {"Trazado":"Desde el entorno de la caja fría hacia el borde sur indicado en el croquis; entrada al subsuelo dentro de la parcela.","Entrada al subsuelo":"Eje aproximado a 1,19 m del lindero; dos tuberías desplazadas ±0,45 m lateralmente.","Terreno exterior":"Nivel provisional prolongado desde la entrada al subsuelo; no se aporta levantamiento exterior ni se amplía la parcela."}
JH_EvidenciaDeMaterial - name: Bastidor metálico · gris; status: provisional; source: Material, espesor, aislamiento y protección pendientes de ingeniería.
JH_CapaBIM - IdentificadorCapa: pipe_gallery; NombreCapa: Galería de nitrógeno · esquema; Funcion: Pórtico metálico de tuberías · 4; VisibilidadInicial: yes
JH_EsquemaProvisional - Estado: No para construcción; Origen: {"documentId":"JH-USER-N2-20260908","title":"Indicación del cliente y croquis sobre el visor · 08/09/2026","date":"2026-09-08","sheet":"Recorrido orientativo señalado en rojo","note":"Diámetros aproximados de 0,50 y 0,20 m solicitados por el cliente. No es un plano de ingeniería."}; DimensionesSupuestas: [{"label":"Separación transversal de pilares","value":2.2,"unit":"m"},{"label":"Perfil gráfico de pilares y travesaños","value":0.16,"unit":"m"},{"label":"Placa / dado orientativo de apoyo","value":0.4,"unit":"m"},{"label":"Criterio","value":"Pórticos laterales y travesaños que envuelven las dos tuberías; sin cálculo estructural","unit":""}]; Posicion: {"Trazado":"Desde el entorno de la caja fría hacia el borde sur indicado en el croquis; entrada al subsuelo dentro de la parcela.","Entrada al subsuelo":"Eje aproximado a 1,19 m del lindero; dos tuberías desplazadas ±0,45 m lateralmente.","Terreno exterior":"Nivel provisional prolongado desde la entrada al subsuelo; no se aporta levantamiento exterior ni se amplía la parcela."}; IncluirEnMediciones: no; Criterio: {"enabled":true,"basis":"Esquema provisional solicitado por el cliente. Trazado, altura, profundidad, soportes, material y conexiones pendientes de plano; no para construcción ni cómputo de cantidades.","pending":["Plano de ruta y servidumbre exterior","Alturas, profundidad y recubrimiento","Clase de tubería, presión, espesor, aislamiento y uniones","Cálculo de soportes, dilatación y conexiones reales"]}

# IfcElementAssembly: Pórtico metálico de tuberías · salida exterior
In: Parcela industrial Jinhong
Description: Cruce subterráneo provisional solicitado por el cliente. Salida al otro lado de la plataforma viaria; cotas, profundidad, soportes y conexión final pendientes del plano definitivo. No para construcción ni cantidades de obra.; PredefinedType: USERDEFINED; Document: Indicación del cliente y croquis sobre el visor · 08/09/2026; Corrección del cliente · cruce subterráneo completo del vial exterior; Group: BIM · Galería de nitrógeno · esquema
JH_CapaBIM - IdentificadorCapa: pipe_gallery; NombreCapa: Galería de nitrógeno · esquema; Funcion: Pórtico metálico de tuberías · salida exterior; VisibilidadInicial: yes
JH_EsquemaProvisional - Estado: No para construcción; Origen: {"documentId":"JH-USER-CROSSING-20260909","title":"Corrección del cliente · cruce subterráneo completo del vial exterior","date":"2026-09-09","sheet":"Croquis rojo sobre el visor con entorno","note":"Entrar al subsuelo dentro de la parcela, atravesar calzada y aceras, y salir al otro lado. Geometría provisional de coordinación; diámetros aproximados 0,50 y 0,20 m."}; DimensionesSupuestas: [{"label":"Separación transversal de pilares","value":2.2,"unit":"m"},{"label":"Perfil gráfico de pilares y travesaños","value":0.16,"unit":"m"},{"label":"Placa / dado orientativo de apoyo","value":0.4,"unit":"m"},{"label":"Criterio","value":"Pórticos laterales y travesaños que envuelven las dos tuberías; sin cálculo estructural","unit":""}]; Posicion: {"Recorrido":"Bajante dentro de la parcela, cruce de toda la calzada y ambas aceras, subida en el margen opuesto.","Salida":"Eje situado aproximadamente 3 m después del borde exterior de la acera opuesta.","Cotas":"Superficie de contexto simplificada; profundidad de visualización, no cálculo de diseño.","Dimensiones":"Diámetros y radios provisionales; conservar hasta recibir plano."}; IncluirEnMediciones: no; Criterio: {"enabled":true,"basis":"Cruce subterráneo provisional solicitado por el cliente. Salida al otro lado de la plataforma viaria; cotas, profundidad, soportes y conexión final pendientes del plano definitivo. No para construcción ni cantidades de obra.","pending":["Plano definitivo de cruce","Profundidad y servicios enterrados","Protección y apoyos","Destino y conexión"]}
JH_InformacionBIM - buildingId: site; buildingName: Urbanización y parcela; level: Exterior · esquema de servicios; category: Pórtico metálico de tuberías · salida exterior; ifcClass: IfcElementAssembly; status: provisional; source: {"documentId":"JH-USER-CROSSING-20260909","title":"Corrección del cliente · cruce subterráneo completo del vial exterior","date":"2026-09-09","sheet":"Croquis rojo sobre el visor con entorno","note":"Entrar al subsuelo dentro de la parcela, atravesar calzada y aceras, y salir al otro lado. Geometría provisional de coordinación; diámetros aproximados 0,50 y 0,20 m."}; material: {"name":"Bastidor metálico · gris","status":"provisional","source":"Material, espesor, aislamiento y protección pendientes de ingeniería."}; dimensions: {"documented":[],"assumed":[{"label":"Separación transversal de pilares","value":2.2,"unit":"m"},{"label":"Perfil gráfico de pilares y travesaños","value":0.16,"unit":"m"},{"label":"Placa / dado orientativo de apoyo","value":0.4,"unit":"m"},{"label":"Criterio","value":"Pórticos laterales y travesaños que envuelven las dos tuberías; sin cálculo estructural","unit":""}],"geometry":[{"label":"Extensión representada X","value":2.630252,"unit":"m"},{"label":"Extensión representada Y","value":0.750403,"unit":"m"},{"label":"Extensión representada Z","value":3.899538,"unit":"m"}]}; appearance: {"profileId":"n2_rack_steel","name":"Bastidor metálico · gris","status":"criterio_visual","basis":"Color y acabado orientativos para distinguir el esquema solicitado; material sin especificación confirmada."}; classification: {"layerId":"pipe_gallery","layerName":"Galería de nitrógeno · esquema","function":"Pórtico metálico de tuberías · salida exterior"}; visualLayer: {"id":"pipe_gallery","name":"Galería de nitrógeno · esquema","defaultVisible":true}; representationKind: esquema_provisional_no_constructivo; conceptual: {"enabled":true,"basis":"Cruce subterráneo provisional solicitado por el cliente. Salida al otro lado de la plataforma viaria; cotas, profundidad, soportes y conexión final pendientes del plano definitivo. No para construcción ni cantidades de obra.","pending":["Plano definitivo de cruce","Profundidad y servicios enterrados","Protección y apoyos","Destino y conexión"]}; positioning: {"Recorrido":"Bajante dentro de la parcela, cruce de toda la calzada y ambas aceras, subida en el margen opuesto.","Salida":"Eje situado aproximadamente 3 m después del borde exterior de la acera opuesta.","Cotas":"Superficie de contexto simplificada; profundidad de visualización, no cálculo de diseño.","Dimensiones":"Diámetros y radios provisionales; conservar hasta recibir plano."}; quantityEligible: no; issues: ["Cruce subterráneo provisional solicitado por el cliente. Salida al otro lado de la plataforma viaria; cotas, profundidad, soportes y conexión final pendientes del plano definitivo. No para construcción ni cantidades de obra."]; rackStationM: 56.6387; rackBeamCenterZM: 3.46773; rackUpperBeamCenterZM: 4.71773; isOutletSupport: yes; geometryMetrics: {"boundingBoxM":{"min":[49.970457,-15.986122,0.89819],"max":[52.600709,-15.235719,4.797728]},"extentsM":[2.630252,0.750403,3.899538],"meshSurfaceM2":10.197659,"meshVolumeM3":0.411278,"closedSolid":true,"basis":"Cruce subterráneo provisional solicitado por el cliente. Salida al otro lado de la plataforma viaria; cotas, profundidad, soportes y conexión final pendientes del plano definitivo. No para construcción ni cantidades de obra."}
JH_Trazabilidad - Origen: Corrección del cliente · cruce subterráneo completo del vial exterior; Estado: Provisional · no para construcción; Capa BIM: Galería de nitrógeno · esquema; Mediciones de obra: Excluido; Identificador: N2-RACK-FRAME-05; Categoria: Pórtico metálico de tuberías · salida exterior; ClaseIFC: IfcElementAssembly; EstadoDeInformacion: provisional; DocumentoFuente: {"documentId":"JH-USER-CROSSING-20260909","title":"Corrección del cliente · cruce subterráneo completo del vial exterior","date":"2026-09-09","sheet":"Croquis rojo sobre el visor con entorno","note":"Entrar al subsuelo dentro de la parcela, atravesar calzada y aceras, y salir al otro lado. Geometría provisional de coordinación; diámetros aproximados 0,50 y 0,20 m."}; IncidenciasPendientes: ["Cruce subterráneo provisional solicitado por el cliente. Salida al otro lado de la plataforma viaria; cotas, profundidad, soportes y conexión final pendientes del plano definitivo. No para construcción ni cantidades de obra."]; UsoDeLasMagnitudes: Cruce subterráneo provisional solicitado por el cliente. Salida al otro lado de la plataforma viaria; cotas, profundidad, soportes y conexión final pendientes del plano definitivo. No para construcción ni cantidades de obra.
JH_CriterioDePosicion - PosicionYEstado: {"Recorrido":"Bajante dentro de la parcela, cruce de toda la calzada y ambas aceras, subida en el margen opuesto.","Salida":"Eje situado aproximadamente 3 m después del borde exterior de la acera opuesta.","Cotas":"Superficie de contexto simplificada; profundidad de visualización, no cálculo de diseño.","Dimensiones":"Diámetros y radios provisionales; conservar hasta recibir plano."}
JH_EvidenciaDeMaterial - name: Bastidor metálico · gris; status: provisional; source: Material, espesor, aislamiento y protección pendientes de ingeniería.

# IfcElementAssembly: Vigas y arriostramiento lateral · tramo 1
In: Parcela industrial Jinhong
Description: Esquema provisional de coordinación autorizado por el cliente. Tuberías, soportes, alumbrado e hidrantes con dimensiones y posiciones orientativas; no para construcción ni cómputo de cantidades.; PredefinedType: USERDEFINED; Document: Indicación del cliente y croquis sobre el visor · 08/09/2026; Group: BIM · Galería de nitrógeno · esquema
JH_InformacionBIM - buildingId: site; buildingName: Urbanización y parcela; level: Exterior · esquema de servicios; category: Vigas y arriostramiento lateral · tramo 1; ifcClass: IfcElementAssembly; status: provisional; source: {"documentId":"JH-USER-N2-20260908","title":"Indicación del cliente y croquis sobre el visor · 08/09/2026","date":"2026-09-08","sheet":"Recorrido orientativo señalado en rojo","note":"Diámetros aproximados de 0,50 y 0,20 m solicitados por el cliente. No es un plano de ingeniería."}; material: {"name":"Bastidor metálico · gris","status":"provisional","source":"Material, espesor, aislamiento y protección pendientes de ingeniería."}; dimensions: {"documented":[],"assumed":[{"label":"Luz gráfica entre pórticos","value":6.0,"unit":"m"},{"label":"Perfil gráfico de largueros","value":0.14,"unit":"m"},{"label":"Perfil gráfico de diagonales","value":0.07,"unit":"m"},{"label":"Criterio","value":"Sin pilares intermedios sobre el vial. Perfiles y luces pendientes de cálculo.","unit":""}],"geometry":[{"label":"Extensión representada X","value":3.135416,"unit":"m"},{"label":"Extensión representada Y","value":6.267854,"unit":"m"},{"label":"Extensión representada Z","value":1.39,"unit":"m"}]}; appearance: {"profileId":"n2_rack_steel","name":"Bastidor metálico · gris","status":"criterio_visual","basis":"Color y acabado orientativos para distinguir el esquema solicitado; material sin especificación confirmada."}; classification: {"layerId":"pipe_gallery","layerName":"Galería de nitrógeno · esquema","function":"Vigas y arriostramiento lateral · tramo 1"}; visualLayer: {"id":"pipe_gallery","name":"Galería de nitrógeno · esquema","defaultVisible":true}; representationKind: esquema_provisional_no_constructivo; conceptual: {"enabled":true,"basis":"Esquema provisional solicitado por el cliente. Trazado, altura, profundidad, soportes, material y conexiones pendientes de plano; no para construcción ni cómputo de cantidades.","pending":["Plano de ruta y servidumbre exterior","Alturas, profundidad y recubrimiento","Clase de tubería, presión, espesor, aislamiento y uniones","Cálculo de soportes, dilatación y conexiones reales"]}; positioning: {"Trazado":"Desde el entorno de la caja fría hacia el borde sur indicado en el croquis; entrada al subsuelo dentro de la parcela.","Entrada al subsuelo":"Eje aproximado a 1,19 m del lindero; dos tuberías desplazadas ±0,45 m lateralmente.","Terreno exterior":"Nivel provisional prolongado desde la entrada al subsuelo; no se aporta levantamiento exterior ni se amplía la parcela."}; quantityEligible: no; issues: ["Esquema provisional solicitado por el cliente. Trazado, altura, profundidad, soportes, material y conexiones pendientes de plano; no para construcción ni cómputo de cantidades.","La posición de la salida exterior y el terreno de contexto son orientativos, sin confirmar propiedad, permisos ni destino de conexión."]; rackStationsM: [6.0,12.0]; geometryMetrics: {"boundingBoxM":{"min":[56.206457,28.449946,6.68],"max":[59.341873,34.7178,8.07]},"extentsM":[3.135416,6.267854,1.39],"meshSurfaceM2":20.50028,"meshVolumeM3":0.590524,"closedSolid":true,"basis":"Esquema provisional de coordinación autorizado por el cliente. Tuberías, soportes, alumbrado e hidrantes con dimensiones y posiciones orientativas; no para construcción ni cómputo de cantidades."}
JH_Trazabilidad - Origen: Croquis e indicación del cliente · 08/09/2026; Estado: Provisional · no para construcción; Capa BIM: Galería de nitrógeno · esquema; Mediciones de obra: Excluido; Identificador: N2-RACK-SPAN-01; Categoria: Vigas y arriostramiento lateral · tramo 1; ClaseIFC: IfcElementAssembly; EstadoDeInformacion: provisional; DocumentoFuente: {"documentId":"JH-USER-N2-20260908","title":"Indicación del cliente y croquis sobre el visor · 08/09/2026","date":"2026-09-08","sheet":"Recorrido orientativo señalado en rojo","note":"Diámetros aproximados de 0,50 y 0,20 m solicitados por el cliente. No es un plano de ingeniería."}; IncidenciasPendientes: ["Esquema provisional solicitado por el cliente. Trazado, altura, profundidad, soportes, material y conexiones pendientes de plano; no para construcción ni cómputo de cantidades.","La posición de la salida exterior y el terreno de contexto son orientativos, sin confirmar propiedad, permisos ni destino de conexión."]; UsoDeLasMagnitudes: Esquema provisional de coordinación autorizado por el cliente. Tuberías, soportes, alumbrado e hidrantes con dimensiones y posiciones orientativas; no para construcción ni cómputo de cantidades.
JH_CriterioDePosicion - PosicionYEstado: {"Trazado":"Desde el entorno de la caja fría hacia el borde sur indicado en el croquis; entrada al subsuelo dentro de la parcela.","Entrada al subsuelo":"Eje aproximado a 1,19 m del lindero; dos tuberías desplazadas ±0,45 m lateralmente.","Terreno exterior":"Nivel provisional prolongado desde la entrada al subsuelo; no se aporta levantamiento exterior ni se amplía la parcela."}
JH_EvidenciaDeMaterial - name: Bastidor metálico · gris; status: provisional; source: Material, espesor, aislamiento y protección pendientes de ingeniería.
JH_CapaBIM - IdentificadorCapa: pipe_gallery; NombreCapa: Galería de nitrógeno · esquema; Funcion: Vigas y arriostramiento lateral · tramo 1; VisibilidadInicial: yes
JH_EsquemaProvisional - Estado: No para construcción; Origen: {"documentId":"JH-USER-N2-20260908","title":"Indicación del cliente y croquis sobre el visor · 08/09/2026","date":"2026-09-08","sheet":"Recorrido orientativo señalado en rojo","note":"Diámetros aproximados de 0,50 y 0,20 m solicitados por el cliente. No es un plano de ingeniería."}; DimensionesSupuestas: [{"label":"Luz gráfica entre pórticos","value":6.0,"unit":"m"},{"label":"Perfil gráfico de largueros","value":0.14,"unit":"m"},{"label":"Perfil gráfico de diagonales","value":0.07,"unit":"m"},{"label":"Criterio","value":"Sin pilares intermedios sobre el vial. Perfiles y luces pendientes de cálculo.","unit":""}]; Posicion: {"Trazado":"Desde el entorno de la caja fría hacia el borde sur indicado en el croquis; entrada al subsuelo dentro de la parcela.","Entrada al subsuelo":"Eje aproximado a 1,19 m del lindero; dos tuberías desplazadas ±0,45 m lateralmente.","Terreno exterior":"Nivel provisional prolongado desde la entrada al subsuelo; no se aporta levantamiento exterior ni se amplía la parcela."}; IncluirEnMediciones: no; Criterio: {"enabled":true,"basis":"Esquema provisional solicitado por el cliente. Trazado, altura, profundidad, soportes, material y conexiones pendientes de plano; no para construcción ni cómputo de cantidades.","pending":["Plano de ruta y servidumbre exterior","Alturas, profundidad y recubrimiento","Clase de tubería, presión, espesor, aislamiento y uniones","Cálculo de soportes, dilatación y conexiones reales"]}

# IfcElementAssembly: Vigas y arriostramiento lateral · tramo 2
In: Parcela industrial Jinhong
Description: Esquema provisional de coordinación autorizado por el cliente. Tuberías, soportes, alumbrado e hidrantes con dimensiones y posiciones orientativas; no para construcción ni cómputo de cantidades.; PredefinedType: USERDEFINED; Document: Indicación del cliente y croquis sobre el visor · 08/09/2026; Group: BIM · Galería de nitrógeno · esquema
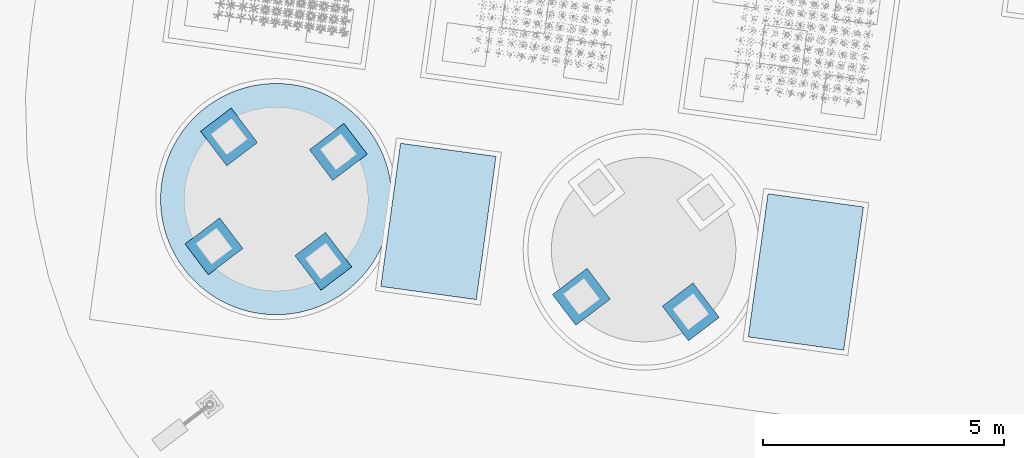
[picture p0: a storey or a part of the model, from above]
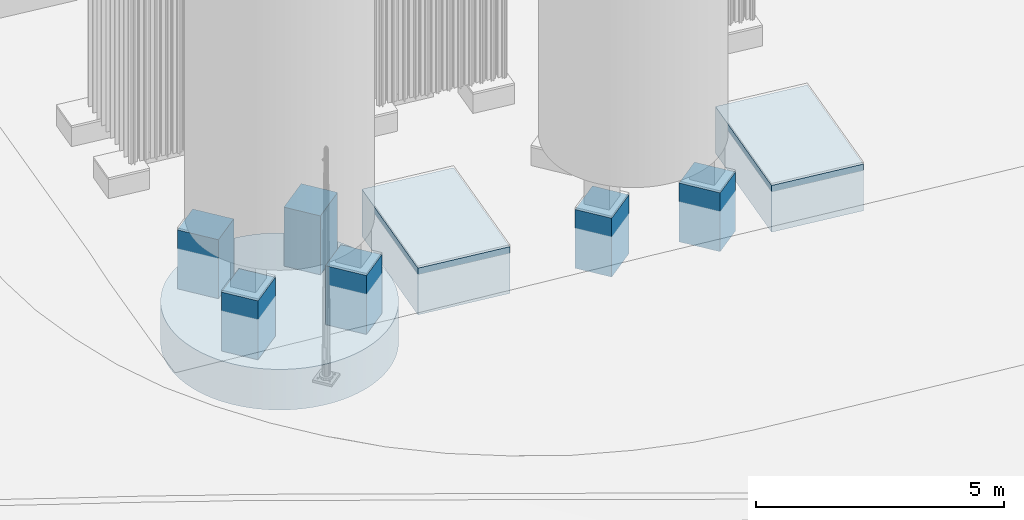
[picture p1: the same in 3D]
Properties of the parts of a building model (IFC4), part 63 of 134

# IfcElementAssembly: Vigas y arriostramiento lateral · tramo 2
JH_InformacionBIM - buildingId: site; buildingName: Urbanización y parcela; level: Exterior · esquema de servicios; category: Vigas y arriostramiento lateral · tramo 2; ifcClass: IfcElementAssembly; status: provisional; source: {"documentId":"JH-USER-N2-20260908","title":"Indicación del cliente y croquis sobre el visor · 08/09/2026","date":"2026-09-08","sheet":"Recorrido orientativo señalado en rojo","note":"Diámetros aproximados de 0,50 y 0,20 m solicitados por el cliente. No es un plano de ingeniería."}; material: {"name":"Bastidor metálico · gris","status":"provisional","source":"Material, espesor, aislamiento y protección pendientes de ingeniería."}; dimensions: {"documented":[],"assumed":[{"label":"Luz gráfica entre pórticos","value":7.3,"unit":"m"},{"label":"Perfil gráfico de largueros","value":0.14,"unit":"m"},{"label":"Perfil gráfico de diagonales","value":0.07,"unit":"m"},{"label":"Criterio","value":"Sin pilares intermedios sobre el vial. Perfiles y luces pendientes de cálculo.","unit":""}],"geometry":[{"label":"Extensión representada X","value":3.312481,"unit":"m"},{"label":"Extensión representada Y","value":7.552945,"unit":"m"},{"label":"Extensión representada Z","value":1.39,"unit":"m"}]}; appearance: {"profileId":"n2_rack_steel","name":"Bastidor metálico · gris","status":"criterio_visual","basis":"Color y acabado orientativos para distinguir el esquema solicitado; material sin especificación confirmada."}; classification: {"layerId":"pipe_gallery","layerName":"Galería de nitrógeno · esquema","function":"Vigas y arriostramiento lateral · tramo 2"}; visualLayer: {"id":"pipe_gallery","name":"Galería de nitrógeno · esquema","defaultVisible":true}; representationKind: esquema_provisional_no_constructivo; conceptual: {"enabled":true,"basis":"Esquema provisional solicitado por el cliente. Trazado, altura, profundidad, soportes, material y conexiones pendientes de plano; no para construcción ni cómputo de cantidades.","pending":["Plano de ruta y servidumbre exterior","Alturas, profundidad y recubrimiento","Clase de tubería, presión, espesor, aislamiento y uniones","Cálculo de soportes, dilatación y conexiones reales"]}; positioning: {"Trazado":"Desde el entorno de la caja fría hacia el borde sur indicado en el croquis; entrada al subsuelo dentro de la parcela.","Entrada al subsuelo":"Eje aproximado a 1,19 m del lindero; dos tuberías desplazadas ±0,45 m lateralmente.","Terreno exterior":"Nivel provisional prolongado desde la entrada al subsuelo; no se aporta levantamiento exterior ni se amplía la parcela."}; quantityEligible: no; issues: ["Esquema provisional solicitado por el cliente. Trazado, altura, profundidad, soportes, material y conexiones pendientes de plano; no para construcción ni cómputo de cantidades.","La posición de la salida exterior y el terreno de contexto son orientativos, sin confirmar propiedad, permisos ni destino de conexión."]; rackStationsM: [12.0,19.3]; geometryMetrics: {"boundingBoxM":{"min":[55.212169,21.219373,6.68],"max":[58.52465,28.772318,8.07]},"extentsM":[3.312481,7.552945,1.39],"meshSurfaceM2":24.842986,"meshVolumeM3":0.717482,"closedSolid":true,"basis":"Esquema provisional de coordinación autorizado por el cliente. Tuberías, soportes, alumbrado e hidrantes con dimensiones y posiciones orientativas; no para construcción ni cómputo de cantidades."}
JH_Trazabilidad - Origen: Croquis e indicación del cliente · 08/09/2026; Estado: Provisional · no para construcción; Capa BIM: Galería de nitrógeno · esquema; Mediciones de obra: Excluido; Identificador: N2-RACK-SPAN-02; Categoria: Vigas y arriostramiento lateral · tramo 2; ClaseIFC: IfcElementAssembly; EstadoDeInformacion: provisional; DocumentoFuente: {"documentId":"JH-USER-N2-20260908","title":"Indicación del cliente y croquis sobre el visor · 08/09/2026","date":"2026-09-08","sheet":"Recorrido orientativo señalado en rojo","note":"Diámetros aproximados de 0,50 y 0,20 m solicitados por el cliente. No es un plano de ingeniería."}; IncidenciasPendientes: ["Esquema provisional solicitado por el cliente. Trazado, altura, profundidad, soportes, material y conexiones pendientes de plano; no para construcción ni cómputo de cantidades.","La posición de la salida exterior y el terreno de contexto son orientativos, sin confirmar propiedad, permisos ni destino de conexión."]; UsoDeLasMagnitudes: Esquema provisional de coordinación autorizado por el cliente. Tuberías, soportes, alumbrado e hidrantes con dimensiones y posiciones orientativas; no para construcción ni cómputo de cantidades.
JH_CriterioDePosicion - PosicionYEstado: {"Trazado":"Desde el entorno de la caja fría hacia el borde sur indicado en el croquis; entrada al subsuelo dentro de la parcela.","Entrada al subsuelo":"Eje aproximado a 1,19 m del lindero; dos tuberías desplazadas ±0,45 m lateralmente.","Terreno exterior":"Nivel provisional prolongado desde la entrada al subsuelo; no se aporta levantamiento exterior ni se amplía la parcela."}
JH_EvidenciaDeMaterial - name: Bastidor metálico · gris; status: provisional; source: Material, espesor, aislamiento y protección pendientes de ingeniería.
JH_CapaBIM - IdentificadorCapa: pipe_gallery; NombreCapa: Galería de nitrógeno · esquema; Funcion: Vigas y arriostramiento lateral · tramo 2; VisibilidadInicial: yes
JH_EsquemaProvisional - Estado: No para construcción; Origen: {"documentId":"JH-USER-N2-20260908","title":"Indicación del cliente y croquis sobre el visor · 08/09/2026","date":"2026-09-08","sheet":"Recorrido orientativo señalado en rojo","note":"Diámetros aproximados de 0,50 y 0,20 m solicitados por el cliente. No es un plano de ingeniería."}; DimensionesSupuestas: [{"label":"Luz gráfica entre pórticos","value":7.3,"unit":"m"},{"label":"Perfil gráfico de largueros","value":0.14,"unit":"m"},{"label":"Perfil gráfico de diagonales","value":0.07,"unit":"m"},{"label":"Criterio","value":"Sin pilares intermedios sobre el vial. Perfiles y luces pendientes de cálculo.","unit":""}]; Posicion: {"Trazado":"Desde el entorno de la caja fría hacia el borde sur indicado en el croquis; entrada al subsuelo dentro de la parcela.","Entrada al subsuelo":"Eje aproximado a 1,19 m del lindero; dos tuberías desplazadas ±0,45 m lateralmente.","Terreno exterior":"Nivel provisional prolongado desde la entrada al subsuelo; no se aporta levantamiento exterior ni se amplía la parcela."}; IncluirEnMediciones: no; Criterio: {"enabled":true,"basis":"Esquema provisional solicitado por el cliente. Trazado, altura, profundidad, soportes, material y conexiones pendientes de plano; no para construcción ni cómputo de cantidades.","pending":["Plano de ruta y servidumbre exterior","Alturas, profundidad y recubrimiento","Clase de tubería, presión, espesor, aislamiento y uniones","Cálculo de soportes, dilatación y conexiones reales"]}

# IfcElementAssembly: Vigas y arriostramiento lateral · tramo 3
In: Parcela industrial Jinhong
Description: Esquema provisional de coordinación autorizado por el cliente. Tuberías, soportes, alumbrado e hidrantes con dimensiones y posiciones orientativas; no para construcción ni cómputo de cantidades.; PredefinedType: USERDEFINED; Document: Indicación del cliente y croquis sobre el visor · 08/09/2026; Group: BIM · Galería de nitrógeno · esquema
JH_InformacionBIM - buildingId: site; buildingName: Urbanización y parcela; level: Exterior · esquema de servicios; category: Vigas y arriostramiento lateral · tramo 3; ifcClass: IfcElementAssembly; status: provisional; source: {"documentId":"JH-USER-N2-20260908","title":"Indicación del cliente y croquis sobre el visor · 08/09/2026","date":"2026-09-08","sheet":"Recorrido orientativo señalado en rojo","note":"Diámetros aproximados de 0,50 y 0,20 m solicitados por el cliente. No es un plano de ingeniería."}; material: {"name":"Bastidor metálico · gris","status":"provisional","source":"Material, espesor, aislamiento y protección pendientes de ingeniería."}; dimensions: {"documented":[],"assumed":[{"label":"Luz gráfica entre pórticos","value":7.55,"unit":"m"},{"label":"Perfil gráfico de largueros","value":0.14,"unit":"m"},{"label":"Perfil gráfico de diagonales","value":0.07,"unit":"m"},{"label":"Criterio","value":"Sin pilares intermedios sobre el vial. Perfiles y luces pendientes de cálculo.","unit":""}],"geometry":[{"label":"Extensión representada X","value":3.357187,"unit":"m"},{"label":"Extensión representada Y","value":7.808714,"unit":"m"},{"label":"Extensión representada Z","value":1.994435,"unit":"m"}]}; appearance: {"profileId":"n2_rack_steel","name":"Bastidor metálico · gris","status":"criterio_visual","basis":"Color y acabado orientativos para distinguir el esquema solicitado; material sin especificación confirmada."}; classification: {"layerId":"pipe_gallery","layerName":"Galería de nitrógeno · esquema","function":"Vigas y arriostramiento lateral · tramo 3"}; visualLayer: {"id":"pipe_gallery","name":"Galería de nitrógeno · esquema","defaultVisible":true}; representationKind: esquema_provisional_no_constructivo; conceptual: {"enabled":true,"basis":"Esquema provisional solicitado por el cliente. Trazado, altura, profundidad, soportes, material y conexiones pendientes de plano; no para construcción ni cómputo de cantidades.","pending":["Plano de ruta y servidumbre exterior","Alturas, profundidad y recubrimiento","Clase de tubería, presión, espesor, aislamiento y uniones","Cálculo de soportes, dilatación y conexiones reales"]}; positioning: {"Trazado":"Desde el entorno de la caja fría hacia el borde sur indicado en el croquis; entrada al subsuelo dentro de la parcela.","Entrada al subsuelo":"Eje aproximado a 1,19 m del lindero; dos tuberías desplazadas ±0,45 m lateralmente.","Terreno exterior":"Nivel provisional prolongado desde la entrada al subsuelo; no se aporta levantamiento exterior ni se amplía la parcela."}; quantityEligible: no; issues: ["Esquema provisional solicitado por el cliente. Trazado, altura, profundidad, soportes, material y conexiones pendientes de plano; no para construcción ni cómputo de cantidades.","La posición de la salida exterior y el terreno de contexto son orientativos, sin confirmar propiedad, permisos ni destino de conexión."]; rackStationsM: [19.3,26.85]; geometryMetrics: {"boundingBoxM":{"min":[54.178502,13.735683,6.075565],"max":[57.535689,21.544397,8.07]},"extentsM":[3.357187,7.808714,1.994435],"meshSurfaceM2":25.773268,"meshVolumeM3":0.744028,"closedSolid":true,"basis":"Esquema provisional de coordinación autorizado por el cliente. Tuberías, soportes, alumbrado e hidrantes con dimensiones y posiciones orientativas; no para construcción ni cómputo de cantidades."}
JH_Trazabilidad - Origen: Croquis e indicación del cliente · 08/09/2026; Estado: Provisional · no para construcción; Capa BIM: Galería de nitrógeno · esquema; Mediciones de obra: Excluido; Identificador: N2-RACK-SPAN-03; Categoria: Vigas y arriostramiento lateral · tramo 3; ClaseIFC: IfcElementAssembly; EstadoDeInformacion: provisional; DocumentoFuente: {"documentId":"JH-USER-N2-20260908","title":"Indicación del cliente y croquis sobre el visor · 08/09/2026","date":"2026-09-08","sheet":"Recorrido orientativo señalado en rojo","note":"Diámetros aproximados de 0,50 y 0,20 m solicitados por el cliente. No es un plano de ingeniería."}; IncidenciasPendientes: ["Esquema provisional solicitado por el cliente. Trazado, altura, profundidad, soportes, material y conexiones pendientes de plano; no para construcción ni cómputo de cantidades.","La posición de la salida exterior y el terreno de contexto son orientativos, sin confirmar propiedad, permisos ni destino de conexión."]; UsoDeLasMagnitudes: Esquema provisional de coordinación autorizado por el cliente. Tuberías, soportes, alumbrado e hidrantes con dimensiones y posiciones orientativas; no para construcción ni cómputo de cantidades.
JH_CriterioDePosicion - PosicionYEstado: {"Trazado":"Desde el entorno de la caja fría hacia el borde sur indicado en el croquis; entrada al subsuelo dentro de la parcela.","Entrada al subsuelo":"Eje aproximado a 1,19 m del lindero; dos tuberías desplazadas ±0,45 m lateralmente.","Terreno exterior":"Nivel provisional prolongado desde la entrada al subsuelo; no se aporta levantamiento exterior ni se amplía la parcela."}
JH_EvidenciaDeMaterial - name: Bastidor metálico · gris; status: provisional; source: Material, espesor, aislamiento y protección pendientes de ingeniería.
JH_CapaBIM - IdentificadorCapa: pipe_gallery; NombreCapa: Galería de nitrógeno · esquema; Funcion: Vigas y arriostramiento lateral · tramo 3; VisibilidadInicial: yes
JH_EsquemaProvisional - Estado: No para construcción; Origen: {"documentId":"JH-USER-N2-20260908","title":"Indicación del cliente y croquis sobre el visor · 08/09/2026","date":"2026-09-08","sheet":"Recorrido orientativo señalado en rojo","note":"Diámetros aproximados de 0,50 y 0,20 m solicitados por el cliente. No es un plano de ingeniería."}; DimensionesSupuestas: [{"label":"Luz gráfica entre pórticos","value":7.55,"unit":"m"},{"label":"Perfil gráfico de largueros","value":0.14,"unit":"m"},{"label":"Perfil gráfico de diagonales","value":0.07,"unit":"m"},{"label":"Criterio","value":"Sin pilares intermedios sobre el vial. Perfiles y luces pendientes de cálculo.","unit":""}]; Posicion: {"Trazado":"Desde el entorno de la caja fría hacia el borde sur indicado en el croquis; entrada al subsuelo dentro de la parcela.","Entrada al subsuelo":"Eje aproximado a 1,19 m del lindero; dos tuberías desplazadas ±0,45 m lateralmente.","Terreno exterior":"Nivel provisional prolongado desde la entrada al subsuelo; no se aporta levantamiento exterior ni se amplía la parcela."}; IncluirEnMediciones: no; Criterio: {"enabled":true,"basis":"Esquema provisional solicitado por el cliente. Trazado, altura, profundidad, soportes, material y conexiones pendientes de plano; no para construcción ni cómputo de cantidades.","pending":["Plano de ruta y servidumbre exterior","Alturas, profundidad y recubrimiento","Clase de tubería, presión, espesor, aislamiento y uniones","Cálculo de soportes, dilatación y conexiones reales"]}

# IfcFireSuppressionTerminal: Hidrante exterior provisional (5)
In: Parcela industrial Jinhong
Description: Esquema provisional de coordinación autorizado por el cliente. Tuberías, soportes, alumbrado e hidrantes con dimensiones y posiciones orientativas; no para construcción ni cómputo de cantidades.; PredefinedType: USERDEFINED; Document: Ubicación aproximada de alumbrado e hidrantes solicitada para visualización; Urbanización existente en el modelo · contexto de implantación; Group: BIM · Hidrantes exteriores
JH_InformacionBIM - buildingId: site; buildingName: Urbanización y parcela; level: Exterior · implantación provisional; category: Hidrante exterior provisional; ifcClass: IfcFireSuppressionTerminal; material: {"name":"No especificado","status":"unknown","source":"Sin ficha de producto confirmada; acabado gráfico de visualización."}; source: {"documentId":"JH-SITE-SERVICES-CONCEPT-20260908","title":"Ubicación aproximada de alumbrado e hidrantes solicitada para visualización","date":"2026-09-08","sheet":"Esquema provisional autorizado; sin plano de implantación de servicios","sourceScope":"Decisiones gráficas de modelado, no especificación del fabricante ni diseño técnico de instalaciones."}; contextSource: {"documentId":"JH-SITE-GROUND-CONTEXT-20260731","title":"Urbanización existente en el modelo · contexto de implantación","date":"2026-07-31","sheet":"Superficies representadas a partir de U004","sourceScope":"Solo contexto de suelo, viales y obstáculos; no documenta posición de luminarias o hidrantes."}; status: provisional; representationKind: conceptualVolume; conceptual: {"enabled":true,"userRequestedProvisional3D":true,"basis":"Propuesta aproximada de colocación en zonas libres junto a viales, autorizada para visualización.","status":"illustrative_not_documented","physicalHeightConfirmed":false,"quantityEligible":false,"notForConstruction":true,"warning":"Ubicación y dimensiones provisionales; no acredita cobertura contra incendios ni cálculo lumínico. Esquema de coordinación, no apto para construcción, compra ni mediciones."}; physicalHeightConfirmed: no; quantityEligible: no; heightStatus: illustrative_not_documented; layerId: fire_safety; classification: {"layerId":"fire_safety","layerName":"Hidrantes exteriores","role":"Hidrante exterior provisional","basis":"Clasificación funcional de un esquema provisional."}; visualLayer: {"id":"fire_safety","name":"Hidrantes exteriores","defaultVisible":true}; appearance: {"profileId":"amenity_v11_hydrant_graphic","name":"Hidrante provisional · rojo gráfico","status":"esquema_provisional","basis":"Rojo de identificación del esquema. No confirma material, revestimiento, caudal, presión ni conexiones.","physicalMaterialUnchanged":true}; heightReference: {"valueM":1.15,"status":"illustrative_not_documented","sourceSupported":false,"sourceRef":"JH-SITE-SERVICES-CONCEPT-20260908","reason":"Altura elegida para esquema aproximado; no procede de una cota de fabricante.","sourceNote":"Ubicación y dimensiones provisionales; no acredita cobertura contra incendios ni cálculo lumínico. Esquema de coordinación, no apto para construcción, compra ni mediciones."}; issues: ["Ubicación y dimensiones provisionales; no acredita cobertura contra incendios ni cálculo lumínico. Esquema de coordinación, no apto para construcción, compra ni mediciones.","No se modelan cimentaciones enterradas, canalizaciones ni conexiones de servicio. Los anclajes visibles son elementos gráficos sin comprobación resistente.","Sin modelo, fabricante o especificación de prestaciones confirmados.","Sin radio de cobertura certificado, caudal, presión, acometida, red de agua o validación de protección contra incendios."]; coverageVerified: no; connectionsModeled: no; hydraulicCalculationProvided: no; lightingCalculationProvided: no
JH_Trazabilidad - Estado: Provisional; Altura ilustrativa (m): 1.15; Alcance: Ubicación y dimensiones provisionales; no acredita cobertura contra incendios ni cálculo lumínico. Esquema de coordinación, no apto para construcción, compra ni mediciones.; Aplicabilidad a mediciones: No; geometría gráfica sin cantidades certificadas.; Categoria: Hidrante exterior provisional; ClaseIFC: IfcFireSuppressionTerminal; EstadoDeInformacion: provisional; DocumentoFuente: {"documentId":"JH-SITE-SERVICES-CONCEPT-20260908","title":"Ubicación aproximada de alumbrado e hidrantes solicitada para visualización","date":"2026-09-08","sheet":"Esquema provisional autorizado; sin plano de implantación de servicios","sourceScope":"Decisiones gráficas de modelado, no especificación del fabricante ni diseño técnico de instalaciones."}; IncidenciasPendientes: ["Ubicación y dimensiones provisionales; no acredita cobertura contra incendios ni cálculo lumínico. Esquema de coordinación, no apto para construcción, compra ni mediciones.","No se modelan cimentaciones enterradas, canalizaciones ni conexiones de servicio. Los anclajes visibles son elementos gráficos sin comprobación resistente.","Sin modelo, fabricante o especificación de prestaciones confirmados.","Sin radio de cobertura certificado, caudal, presión, acometida, red de agua o validación de protección contra incendios."]; UsoDeLasMagnitudes: Esquema provisional de coordinación autorizado por el cliente. Tuberías, soportes, alumbrado e hidrantes con dimensiones y posiciones orientativas; no para construcción ni cómputo de cantidades.
JH_EvidenciaDeMaterial - name: No especificado; status: unknown; source: Sin ficha de producto confirmada; acabado gráfico de visualización.
JH_CapaBIM - IdentificadorCapa: fire_safety; NombreCapa: Hidrantes exteriores; Funcion: Hidrante exterior provisional; VisibilidadInicial: yes
JH_EsquemaProvisional - Estado: No para construcción; Origen: {"documentId":"JH-SITE-SERVICES-CONCEPT-20260908","title":"Ubicación aproximada de alumbrado e hidrantes solicitada para visualización","date":"2026-09-08","sheet":"Esquema provisional autorizado; sin plano de implantación de servicios","sourceScope":"Decisiones gráficas de modelado, no especificación del fabricante ni diseño técnico de instalaciones."}; IncluirEnMediciones: no; Criterio: {"enabled":true,"userRequestedProvisional3D":true,"basis":"Propuesta aproximada de colocación en zonas libres junto a viales, autorizada para visualización.","status":"illustrative_not_documented","physicalHeightConfirmed":false,"quantityEligible":false,"notForConstruction":true,"warning":"Ubicación y dimensiones provisionales; no acredita cobertura contra incendios ni cálculo lumínico. Esquema de coordinación, no apto para construcción, compra ni mediciones."}
Name | dimensions | visualizationIdentity | positioning = PosicionYEstado = Posicion | geometryMetrics | placementEvidence | Ubicación | Identificador | DimensionesSupuestas
Hidrante H01 · provisional | {"documented":[],"assumed":[{"label":"Altura total ilustrativa sobre el terreno","value":1.15,"unit":"m","status":"supuesto","source":"JH-SITE-SERVICES-CONCEPT-20260908"},{"label":"Posición gráfica X local","value":13.0,"unit":"m","status":"supuesto","source":"JH-SITE-SERVICES-CONCEPT-20260908"},{"label":"Posición gráfica Y local","value":97.6,"unit":"m","status":"supuesto","source":"JH-SITE-SERVICES-CONCEPT-20260908"},{"label":"Diámetro gráfico del cuerpo principal","value":0.19,"unit":"m","status":"supuesto","source":"JH-SITE-SERVICES-CONCEPT-20260908"},{"label":"Diámetro gráfico de la brida inferior","value":0.34,"unit":"m","status":"supuesto","source":"JH-SITE-SERVICES-CONCEPT-20260908"},{"label":"Salidas y tapas","value":"Tres salidas esquemáticas; sus formas no identifican DN, rosca, racor o conexión de fabricante","unit":"","status":"supuesto","source":"JH-SITE-SERVICES-CONCEPT-20260908"},{"label":"Partes menores","value":"Cúpula, tapas, bridas, tuercas y fijaciones de representación; sin especificación técnica","unit":"","status":"supuesto","source":"JH-SITE-SERVICES-CONCEPT-20260908"}],"geometry":[{"label":"Extensión gráfica en X","value":0.62979,"unit":"m","status":"derivado_del_esquema"},{"label":"Extensión gráfica en Y","value":0.498525,"unit":"m","status":"derivado_del_esquema"},{"label":"Extensión gráfica en Z","value":1.15,"unit":"m","status":"derivado_del_esquema"},{"label":"Cota inferior local de visualización","value":0.737869,"unit":"m","status":"datum_provisional"}],"notes":["Ubicación y dimensiones provisionales; no acredita cobertura contra incendios ni cálculo lumínico. Esquema de coordinación, no apto para construcción, compra ni mediciones."]} | {"elementId":"SITE-HYDRANT-01","ifcGuid":"2RT6aCbH5R6xU1VSOTeffn","ifcClass":"IfcFireSuppressionTerminal","buildingId":"site","buildingName":"Urbanización y parcela","sourceDocumentId":"JH-SITE-SERVICES-CONCEPT-20260908","sourceRepresentationKind":"conceptualVolume"} | {"Ubicación":"Entorno del acceso y oficinas","Sistema de coordenadas":"Modelo local en metros; origen horizontal ETRS89 / UTM 29N 729400 / 4301550 m","Base representada (X, Y, Z)":[13.0,97.6,0.737869],"Superficie de apoyo":"site_002","Criterio de cota":"Interpolación sobre triángulos del jardín ya representado; datum absoluto pendiente de confirmación.","Orientación":"Brazo o cara principal orientado hacia el borde de vial más próximo, solo para visualización.","Separación gráfica al vial (m)":0.698717,"Elemento existente próximo":"office_0254","Separación gráfica al elemento (m)":5.377593} | {"boundingBoxM":{"min":[12.685105,97.269891,0.737869],"max":[13.314895,97.768416,1.887869]},"extentsM":[0.62979,0.498525,1.15],"meshSurfaceM2":1.775132,"meshVolumeM3":0.054538,"closedSolid":true,"basis":"Esquema provisional de coordinación autorizado por el cliente. Tuberías, soportes, alumbrado e hidrantes con dimensiones y posiciones orientativas; no para construcción ni cómputo de cantidades."} | {"location":"Entorno del acceso y oficinas","coordinateSystem":"Modelo local en metros; origen horizontal ETRS89 / UTM 29N 729400 / 4301550 m","modelBaseM":[13.0,97.6,0.737869],"groundObjectId":"site_002","groundBasis":"Interpolación sobre triángulos del jardín ya representado; datum absoluto pendiente de confirmación.","orientationBasis":"Brazo o cara principal orientado hacia el borde de vial más próximo, solo para visualización.","roadClearanceOfGraphicFootprintM":0.698717,"nearestExistingObjectId":"office_0254","graphicClearanceToNearestExistingObjectM":5.377593} | Entorno del acceso y oficinas | SITE-HYDRANT-01 | [{"label":"Altura total ilustrativa sobre el terreno","value":1.15,"unit":"m","status":"supuesto","source":"JH-SITE-SERVICES-CONCEPT-20260908"},{"label":"Posición gráfica X local","value":13.0,"unit":"m","status":"supuesto","source":"JH-SITE-SERVICES-CONCEPT-20260908"},{"label":"Posición gráfica Y local","value":97.6,"unit":"m","status":"supuesto","source":"JH-SITE-SERVICES-CONCEPT-20260908"},{"label":"Diámetro gráfico del cuerpo principal","value":0.19,"unit":"m","status":"supuesto","source":"JH-SITE-SERVICES-CONCEPT-20260908"},{"label":"Diámetro gráfico de la brida inferior","value":0.34,"unit":"m","status":"supuesto","source":"JH-SITE-SERVICES-CONCEPT-20260908"},{"label":"Salidas y tapas","value":"Tres salidas esquemáticas; sus formas no identifican DN, rosca, racor o conexión de fabricante","unit":"","status":"supuesto","source":"JH-SITE-SERVICES-CONCEPT-20260908"},{"label":"Partes menores","value":"Cúpula, tapas, bridas, tuercas y fijaciones de representación; sin especificación técnica","unit":"","status":"supuesto","source":"JH-SITE-SERVICES-CONCEPT-20260908"}]
Hidrante H02 · provisional | {"documented":[],"assumed":[{"label":"Altura total ilustrativa sobre el terreno","value":1.15,"unit":"m","status":"supuesto","source":"JH-SITE-SERVICES-CONCEPT-20260908"},{"label":"Posición gráfica X local","value":23.5,"unit":"m","status":"supuesto","source":"JH-SITE-SERVICES-CONCEPT-20260908"},{"label":"Posición gráfica Y local","value":50.0,"unit":"m","status":"supuesto","source":"JH-SITE-SERVICES-CONCEPT-20260908"},{"label":"Diámetro gráfico del cuerpo principal","value":0.19,"unit":"m","status":"supuesto","source":"JH-SITE-SERVICES-CONCEPT-20260908"},{"label":"Diámetro gráfico de la brida inferior","value":0.34,"unit":"m","status":"supuesto","source":"JH-SITE-SERVICES-CONCEPT-20260908"},{"label":"Salidas y tapas","value":"Tres salidas esquemáticas; sus formas no identifican DN, rosca, racor o conexión de fabricante","unit":"","status":"supuesto","source":"JH-SITE-SERVICES-CONCEPT-20260908"},{"label":"Partes menores","value":"Cúpula, tapas, bridas, tuercas y fijaciones de representación; sin especificación técnica","unit":"","status":"supuesto","source":"JH-SITE-SERVICES-CONCEPT-20260908"}],"geometry":[{"label":"Extensión gráfica en X","value":0.498514,"unit":"m","status":"derivado_del_esquema"},{"label":"Extensión gráfica en Y","value":0.62978,"unit":"m","status":"derivado_del_esquema"},{"label":"Extensión gráfica en Z","value":1.15,"unit":"m","status":"derivado_del_esquema"},{"label":"Cota inferior local de visualización","value":0.928149,"unit":"m","status":"datum_provisional"}],"notes":["Ubicación y dimensiones provisionales; no acredita cobertura contra incendios ni cálculo lumínico. Esquema de coordinación, no apto para construcción, compra ni mediciones."]} | {"elementId":"SITE-HYDRANT-02","ifcGuid":"1FxLq1h2PPaut3uXJrPnx_","ifcClass":"IfcFireSuppressionTerminal","buildingId":"site","buildingName":"Urbanización y parcela","sourceDocumentId":"JH-SITE-SERVICES-CONCEPT-20260908","sourceRepresentationKind":"conceptualVolume"} | {"Ubicación":"Jardín oeste junto a equipos","Sistema de coordenadas":"Modelo local en metros; origen horizontal ETRS89 / UTM 29N 729400 / 4301550 m","Base representada (X, Y, Z)":[23.5,50.0,0.928149],"Superficie de apoyo":"site_002","Criterio de cota":"Interpolación sobre triángulos del jardín ya representado; datum absoluto pendiente de confirmación.","Orientación":"Brazo o cara principal orientado hacia el borde de vial más próximo, solo para visualización.","Separación gráfica al vial (m)":3.326827,"Elemento existente próximo":"found_0904_f664036c7b87c2","Separación gráfica al elemento (m)":12.603634} | {"boundingBoxM":{"min":[23.33159,49.68511,0.928149],"max":[23.830104,50.31489,2.078149]},"extentsM":[0.498514,0.62978,1.15],"meshSurfaceM2":1.775132,"meshVolumeM3":0.054538,"closedSolid":true,"basis":"Esquema provisional de coordinación autorizado por el cliente. Tuberías, soportes, alumbrado e hidrantes con dimensiones y posiciones orientativas; no para construcción ni cómputo de cantidades."} | {"location":"Jardín oeste junto a equipos","coordinateSystem":"Modelo local en metros; origen horizontal ETRS89 / UTM 29N 729400 / 4301550 m","modelBaseM":[23.5,50.0,0.928149],"groundObjectId":"site_002","groundBasis":"Interpolación sobre triángulos del jardín ya representado; datum absoluto pendiente de confirmación.","orientationBasis":"Brazo o cara principal orientado hacia el borde de vial más próximo, solo para visualización.","roadClearanceOfGraphicFootprintM":3.326827,"nearestExistingObjectId":"found_0904_f664036c7b87c2","graphicClearanceToNearestExistingObjectM":12.603634} | Jardín oeste junto a equipos | SITE-HYDRANT-02 | [{"label":"Altura total ilustrativa sobre el terreno","value":1.15,"unit":"m","status":"supuesto","source":"JH-SITE-SERVICES-CONCEPT-20260908"},{"label":"Posición gráfica X local","value":23.5,"unit":"m","status":"supuesto","source":"JH-SITE-SERVICES-CONCEPT-20260908"},{"label":"Posición gráfica Y local","value":50.0,"unit":"m","status":"supuesto","source":"JH-SITE-SERVICES-CONCEPT-20260908"},{"label":"Diámetro gráfico del cuerpo principal","value":0.19,"unit":"m","status":"supuesto","source":"JH-SITE-SERVICES-CONCEPT-20260908"},{"label":"Diámetro gráfico de la brida inferior","value":0.34,"unit":"m","status":"supuesto","source":"JH-SITE-SERVICES-CONCEPT-20260908"},{"label":"Salidas y tapas","value":"Tres salidas esquemáticas; sus formas no identifican DN, rosca, racor o conexión de fabricante","unit":"","status":"supuesto","source":"JH-SITE-SERVICES-CONCEPT-20260908"},{"label":"Partes menores","value":"Cúpula, tapas, bridas, tuercas y fijaciones de representación; sin especificación técnica","unit":"","status":"supuesto","source":"JH-SITE-SERVICES-CONCEPT-20260908"}]
Hidrante H03 · provisional | {"documented":[],"assumed":[{"label":"Altura total ilustrativa sobre el terreno","value":1.15,"unit":"m","status":"supuesto","source":"JH-SITE-SERVICES-CONCEPT-20260908"},{"label":"Posición gráfica X local","value":22.5,"unit":"m","status":"supuesto","source":"JH-SITE-SERVICES-CONCEPT-20260908"},{"label":"Posición gráfica Y local","value":23.5,"unit":"m","status":"supuesto","source":"JH-SITE-SERVICES-CONCEPT-20260908"},{"label":"Diámetro gráfico del cuerpo principal","value":0.19,"unit":"m","status":"supuesto","source":"JH-SITE-SERVICES-CONCEPT-20260908"},{"label":"Diámetro gráfico de la brida inferior","value":0.34,"unit":"m","status":"supuesto","source":"JH-SITE-SERVICES-CONCEPT-20260908"},{"label":"Salidas y tapas","value":"Tres salidas esquemáticas; sus formas no identifican DN, rosca, racor o conexión de fabricante","unit":"","status":"supuesto","source":"JH-SITE-SERVICES-CONCEPT-20260908"},{"label":"Partes menores","value":"Cúpula, tapas, bridas, tuercas y fijaciones de representación; sin especificación técnica","unit":"","status":"supuesto","source":"JH-SITE-SERVICES-CONCEPT-20260908"}],"geometry":[{"label":"Extensión gráfica en X","value":0.498275,"unit":"m","status":"derivado_del_esquema"},{"label":"Extensión gráfica en Y","value":0.62954,"unit":"m","status":"derivado_del_esquema"},{"label":"Extensión gráfica en Z","value":1.15,"unit":"m","status":"derivado_del_esquema"},{"label":"Cota inferior local de visualización","value":1.039578,"unit":"m","status":"datum_provisional"}],"notes":["Ubicación y dimensiones provisionales; no acredita cobertura contra incendios ni cálculo lumínico. Esquema de coordinación, no apto para construcción, compra ni mediciones."]} | {"elementId":"SITE-HYDRANT-03","ifcGuid":"1C$2WaDWXL5Pe3JI7XRJyE","ifcClass":"IfcFireSuppressionTerminal","buildingId":"site","buildingName":"Urbanización y parcela","sourceDocumentId":"JH-SITE-SERVICES-CONCEPT-20260908","sourceRepresentationKind":"conceptualVolume"} | {"Ubicación":"Entorno sur de la sala de bombas","Sistema de coordenadas":"Modelo local en metros; origen horizontal ETRS89 / UTM 29N 729400 / 4301550 m","Base representada (X, Y, Z)":[22.5,23.5,1.039578],"Superficie de apoyo":"site_002","Criterio de cota":"Interpolación sobre triángulos del jardín ya representado; datum absoluto pendiente de confirmación.","Orientación":"Brazo o cara principal orientado hacia el borde de vial más próximo, solo para visualización.","Separación gráfica al vial (m)":0.679438,"Elemento existente próximo":"pump_house_0058","Separación gráfica al elemento (m)":3.736026} | {"boundingBoxM":{"min":[22.331712,23.18523,1.039578],"max":[22.829987,23.81477,2.189578]},"extentsM":[0.498275,0.62954,1.15],"meshSurfaceM2":1.775131,"meshVolumeM3":0.054538,"closedSolid":true,"basis":"Esquema provisional de coordinación autorizado por el cliente. Tuberías, soportes, alumbrado e hidrantes con dimensiones y posiciones orientativas; no para construcción ni cómputo de cantidades."} | {"location":"Entorno sur de la sala de bombas","coordinateSystem":"Modelo local en metros; origen horizontal ETRS89 / UTM 29N 729400 / 4301550 m","modelBaseM":[22.5,23.5,1.039578],"groundObjectId":"site_002","groundBasis":"Interpolación sobre triángulos del jardín ya representado; datum absoluto pendiente de confirmación.","orientationBasis":"Brazo o cara principal orientado hacia el borde de vial más próximo, solo para visualización.","roadClearanceOfGraphicFootprintM":0.679438,"nearestExistingObjectId":"pump_house_0058","graphicClearanceToNearestExistingObjectM":3.736026} | Entorno sur de la sala de bombas | SITE-HYDRANT-03 | [{"label":"Altura total ilustrativa sobre el terreno","value":1.15,"unit":"m","status":"supuesto","source":"JH-SITE-SERVICES-CONCEPT-20260908"},{"label":"Posición gráfica X local","value":22.5,"unit":"m","status":"supuesto","source":"JH-SITE-SERVICES-CONCEPT-20260908"},{"label":"Posición gráfica Y local","value":23.5,"unit":"m","status":"supuesto","source":"JH-SITE-SERVICES-CONCEPT-20260908"},{"label":"Diámetro gráfico del cuerpo principal","value":0.19,"unit":"m","status":"supuesto","source":"JH-SITE-SERVICES-CONCEPT-20260908"},{"label":"Diámetro gráfico de la brida inferior","value":0.34,"unit":"m","status":"supuesto","source":"JH-SITE-SERVICES-CONCEPT-20260908"},{"label":"Salidas y tapas","value":"Tres salidas esquemáticas; sus formas no identifican DN, rosca, racor o conexión de fabricante","unit":"","status":"supuesto","source":"JH-SITE-SERVICES-CONCEPT-20260908"},{"label":"Partes menores","value":"Cúpula, tapas, bridas, tuercas y fijaciones de representación; sin especificación técnica","unit":"","status":"supuesto","source":"JH-SITE-SERVICES-CONCEPT-20260908"}]
Hidrante H04 · provisional | {"documented":[],"assumed":[{"label":"Altura total ilustrativa sobre el terreno","value":1.15,"unit":"m","status":"supuesto","source":"JH-SITE-SERVICES-CONCEPT-20260908"},{"label":"Posición gráfica X local","value":111.0,"unit":"m","status":"supuesto","source":"JH-SITE-SERVICES-CONCEPT-20260908"},{"label":"Posición gráfica Y local","value":16.5,"unit":"m","status":"supuesto","source":"JH-SITE-SERVICES-CONCEPT-20260908"},{"label":"Diámetro gráfico del cuerpo principal","value":0.19,"unit":"m","status":"supuesto","source":"JH-SITE-SERVICES-CONCEPT-20260908"},{"label":"Diámetro gráfico de la brida inferior","value":0.34,"unit":"m","status":"supuesto","source":"JH-SITE-SERVICES-CONCEPT-20260908"},{"label":"Salidas y tapas","value":"Tres salidas esquemáticas; sus formas no identifican DN, rosca, racor o conexión de fabricante","unit":"","status":"supuesto","source":"JH-SITE-SERVICES-CONCEPT-20260908"},{"label":"Partes menores","value":"Cúpula, tapas, bridas, tuercas y fijaciones de representación; sin especificación técnica","unit":"","status":"supuesto","source":"JH-SITE-SERVICES-CONCEPT-20260908"}],"geometry":[{"label":"Extensión gráfica en X","value":0.609548,"unit":"m","status":"derivado_del_esquema"},{"label":"Extensión gráfica en Y","value":0.489469,"unit":"m","status":"derivado_del_esquema"},{"label":"Extensión gráfica en Z","value":1.15,"unit":"m","status":"derivado_del_esquema"},{"label":"Cota inferior local de visualización","value":1.910612,"unit":"m","status":"datum_provisional"}],"notes":["Ubicación y dimensiones provisionales; no acredita cobertura contra incendios ni cálculo lumínico. Esquema de coordinación, no apto para construcción, compra ni mediciones."]} | {"elementId":"SITE-HYDRANT-04","ifcGuid":"3nf9Il3sPMsBjt5o1IQioc","ifcClass":"IfcFireSuppressionTerminal","buildingId":"site","buildingName":"Urbanización y parcela","sourceDocumentId":"JH-SITE-SERVICES-CONCEPT-20260908","sourceRepresentationKind":"conceptualVolume"} | {"Ubicación":"Jardín sureste","Sistema de coordenadas":"Modelo local en metros; origen horizontal ETRS89 / UTM 29N 729400 / 4301550 m","Base representada (X, Y, Z)":[111.0,16.5,1.910612],"Superficie de apoyo":"site_001","Criterio de cota":"Interpolación sobre triángulos del jardín ya representado; datum absoluto pendiente de confirmación.","Orientación":"Brazo o cara principal orientado hacia el borde de vial más próximo, solo para visualización.","Separación gráfica al vial (m)":2.354403,"Elemento existente próximo":"FENCE-21B33-1-BASE","Separación gráfica al elemento (m)":11.267232} | {"boundingBoxM":{"min":[110.695226,16.180192,1.910612],"max":[111.304774,16.669661,3.060612]},"extentsM":[0.609548,0.489469,1.15],"meshSurfaceM2":1.775132,"meshVolumeM3":0.054538,"closedSolid":true,"basis":"Esquema provisional de coordinación autorizado por el cliente. Tuberías, soportes, alumbrado e hidrantes con dimensiones y posiciones orientativas; no para construcción ni cómputo de cantidades."} | {"location":"Jardín sureste","coordinateSystem":"Modelo local en metros; origen horizontal ETRS89 / UTM 29N 729400 / 4301550 m","modelBaseM":[111.0,16.5,1.910612],"groundObjectId":"site_001","groundBasis":"Interpolación sobre triángulos del jardín ya representado; datum absoluto pendiente de confirmación.","orientationBasis":"Brazo o cara principal orientado hacia el borde de vial más próximo, solo para visualización.","roadClearanceOfGraphicFootprintM":2.354403,"nearestExistingObjectId":"FENCE-21B33-1-BASE","graphicClearanceToNearestExistingObjectM":11.267232} | Jardín sureste | SITE-HYDRANT-04 | [{"label":"Altura total ilustrativa sobre el terreno","value":1.15,"unit":"m","status":"supuesto","source":"JH-SITE-SERVICES-CONCEPT-20260908"},{"label":"Posición gráfica X local","value":111.0,"unit":"m","status":"supuesto","source":"JH-SITE-SERVICES-CONCEPT-20260908"},{"label":"Posición gráfica Y local","value":16.5,"unit":"m","status":"supuesto","source":"JH-SITE-SERVICES-CONCEPT-20260908"},{"label":"Diámetro gráfico del cuerpo principal","value":0.19,"unit":"m","status":"supuesto","source":"JH-SITE-SERVICES-CONCEPT-20260908"},{"label":"Diámetro gráfico de la brida inferior","value":0.34,"unit":"m","status":"supuesto","source":"JH-SITE-SERVICES-CONCEPT-20260908"},{"label":"Salidas y tapas","value":"Tres salidas esquemáticas; sus formas no identifican DN, rosca, racor o conexión de fabricante","unit":"","status":"supuesto","source":"JH-SITE-SERVICES-CONCEPT-20260908"},{"label":"Partes menores","value":"Cúpula, tapas, bridas, tuercas y fijaciones de representación; sin especificación técnica","unit":"","status":"supuesto","source":"JH-SITE-SERVICES-CONCEPT-20260908"}]
Hidrante H05 · provisional | {"documented":[],"assumed":[{"label":"Altura total ilustrativa sobre el terreno","value":1.15,"unit":"m","status":"supuesto","source":"JH-SITE-SERVICES-CONCEPT-20260908"},{"label":"Posición gráfica X local","value":118.0,"unit":"m","status":"supuesto","source":"JH-SITE-SERVICES-CONCEPT-20260908"},{"label":"Posición gráfica Y local","value":80.0,"unit":"m","status":"supuesto","source":"JH-SITE-SERVICES-CONCEPT-20260908"},{"label":"Diámetro gráfico del cuerpo principal","value":0.19,"unit":"m","status":"supuesto","source":"JH-SITE-SERVICES-CONCEPT-20260908"},{"label":"Diámetro gráfico de la brida inferior","value":0.34,"unit":"m","status":"supuesto","source":"JH-SITE-SERVICES-CONCEPT-20260908"},{"label":"Salidas y tapas","value":"Tres salidas esquemáticas; sus formas no identifican DN, rosca, racor o conexión de fabricante","unit":"","status":"supuesto","source":"JH-SITE-SERVICES-CONCEPT-20260908"},{"label":"Partes menores","value":"Cúpula, tapas, bridas, tuercas y fijaciones de representación; sin especificación técnica","unit":"","status":"supuesto","source":"JH-SITE-SERVICES-CONCEPT-20260908"}],"geometry":[{"label":"Extensión gráfica en X","value":0.573104,"unit":"m","status":"derivado_del_esquema"},{"label":"Extensión gráfica en Y","value":0.497937,"unit":"m","status":"derivado_del_esquema"},{"label":"Extensión gráfica en Z","value":1.15,"unit":"m","status":"derivado_del_esquema"},{"label":"Cota inferior local de visualización","value":2.574219,"unit":"m","status":"datum_provisional"}],"notes":["Ubicación y dimensiones provisionales; no acredita cobertura contra incendios ni cálculo lumínico. Esquema de coordinación, no apto para construcción, compra ni mediciones."]} | {"elementId":"SITE-HYDRANT-05","ifcGuid":"3VdzIoZo5VfgeikQo5OFLU","ifcClass":"IfcFireSuppressionTerminal","buildingId":"site","buildingName":"Urbanización y parcela","sourceDocumentId":"JH-SITE-SERVICES-CONCEPT-20260908","sourceRepresentationKind":"conceptualVolume"} | {"Ubicación":"Jardín noreste","Sistema de coordenadas":"Modelo local en metros; origen horizontal ETRS89 / UTM 29N 729400 / 4301550 m","Base representada (X, Y, Z)":[118.0,80.0,2.574219],"Superficie de apoyo":"site_001","Criterio de cota":"Interpolación sobre triángulos del jardín ya representado; datum absoluto pendiente de confirmación.","Orientación":"Brazo o cara principal orientado hacia el borde de vial más próximo, solo para visualización.","Separación gráfica al vial (m)":4.308926,"Elemento existente próximo":"FENCE-21B1A-1-BASE","Separación gráfica al elemento (m)":12.531559} | {"boundingBoxM":{"min":[117.713448,79.803296,2.574219],"max":[118.286552,80.301233,3.724219]},"extentsM":[0.573104,0.497937,1.15],"meshSurfaceM2":1.775131,"meshVolumeM3":0.054538,"closedSolid":true,"basis":"Esquema provisional de coordinación autorizado por el cliente. Tuberías, soportes, alumbrado e hidrantes con dimensiones y posiciones orientativas; no para construcción ni cómputo de cantidades."} | {"location":"Jardín noreste","coordinateSystem":"Modelo local en metros; origen horizontal ETRS89 / UTM 29N 729400 / 4301550 m","modelBaseM":[118.0,80.0,2.574219],"groundObjectId":"site_001","groundBasis":"Interpolación sobre triángulos del jardín ya representado; datum absoluto pendiente de confirmación.","orientationBasis":"Brazo o cara principal orientado hacia el borde de vial más próximo, solo para visualización.","roadClearanceOfGraphicFootprintM":4.308926,"nearestExistingObjectId":"FENCE-21B1A-1-BASE","graphicClearanceToNearestExistingObjectM":12.531559} | Jardín noreste | SITE-HYDRANT-05 | [{"label":"Altura total ilustrativa sobre el terreno","value":1.15,"unit":"m","status":"supuesto","source":"JH-SITE-SERVICES-CONCEPT-20260908"},{"label":"Posición gráfica X local","value":118.0,"unit":"m","status":"supuesto","source":"JH-SITE-SERVICES-CONCEPT-20260908"},{"label":"Posición gráfica Y local","value":80.0,"unit":"m","status":"supuesto","source":"JH-SITE-SERVICES-CONCEPT-20260908"},{"label":"Diámetro gráfico del cuerpo principal","value":0.19,"unit":"m","status":"supuesto","source":"JH-SITE-SERVICES-CONCEPT-20260908"},{"label":"Diámetro gráfico de la brida inferior","value":0.34,"unit":"m","status":"supuesto","source":"JH-SITE-SERVICES-CONCEPT-20260908"},{"label":"Salidas y tapas","value":"Tres salidas esquemáticas; sus formas no identifican DN, rosca, racor o conexión de fabricante","unit":"","status":"supuesto","source":"JH-SITE-SERVICES-CONCEPT-20260908"},{"label":"Partes menores","value":"Cúpula, tapas, bridas, tuercas y fijaciones de representación; sin especificación técnica","unit":"","status":"supuesto","source":"JH-SITE-SERVICES-CONCEPT-20260908"}]

# IfcFooting (214)
PredefinedType: PAD_FOOTING
JH_InformacionBIM - ifcClass: IfcFooting; visualLayer: {"id":"foundations","name":"Cimentaciones"}; componentSeparation: {"status":"objeto_independiente","note":"Control de visibilidad del objeto completo; la clasificación no altera la malla."}; layerId: foundations
JH_Trazabilidad - Capa BIM: Cimentaciones; Estado del acabado: criterio_visual; ClaseIFC: IfcFooting; UsoDeLasMagnitudes: Geometría de coordinación. Los volúmenes de referencia y subcomponentes no son cantidades de material ni componentes de fabricación certificados.
JH_CapaBIM - IdentificadorCapa: foundations; NombreCapa: Cimentaciones; VisibilidadInicial: yes
JH_AcabadoVisual - Metallicidad: 0; Estado: criterio_visual; Referencia: Interpretación visual del material documental; el acabado, tono y parámetros PBR no son una especificación contractual.; Nota: La apariencia no certifica el material físico ni el acabado de fabricación.
Name | In | Description = category = Categoria = Funcion | Document | ExtensionX (m) | ExtensionY (m) | ExtensionZ (m) | SuperficieDeLaMalla (m2) | VolumenGeometrico (m3) | buildingId | buildingName | material | dimensions | JH_InformacionBIM, source = DocumentoFuente | JH_InformacionBIM, status = EstadoDeInformacion | issues = IncidenciasPendientes | positioning = PosicionYEstado | geometryMetrics | materialAppearance | visualizationIdentity | classification | appearance | Volumen geométrico (m³) | JH_Trazabilidad, Material = name | Acabado de visualización = Acabado | Identificador | JH_EvidenciaDeMaterial, source | JH_EvidenciaDeMaterial, status | Perfil | ColorRGB | Rugosidad | Group | Extensión de la malla en X (m) | Extensión de la malla en Y (m) | Extensión de la malla en Z (m) = Espesor o altura real de sección (m) | Cota inferior de visualización (m) | Cota superior de visualización (m) | assemblyId = Conjunto de cimentación | equipmentIds | supportPositionIds | sectionRef = Sección de referencia | sourceCadHandles | stableElementKey | representationKind | geometryStatus | Equipos asociados | Documento de origen | Identificadores CAD de referencia | Cota inferior relativa (m) = Cota inferior relativa adoptada (m) | Cota superior relativa (m) = Cota superior relativa adoptada (m) | Área de planta (m²) | Referencia vertical | Implantación para visualización | Estado de la geometría | Extensión local X (m) | Extensión local Y (m) | Incidencias de origen
Sala de bombas contra incendios · zapata aislada BASE1 · 1 | Planta baja | Zapata aislada | Planos de estructura de la sala de bombas contra incendios | 2.25377 | 2.25377 | 0.7 | 13.6 | 2.8 | pump_house | Sala de bombas contra incendios | {"name":"Hormigón armado HA-30","source":"EST-SB-20260710 · Estructura A201 / p. 4; nota de resistencia de zapatas y vigas de atado","status":"known"} | {"documented":[{"label":"Cota inferior absoluta","value":284.05,"unit":"m","source":"EST-SB-20260710 · Estructura A201 / p. 4","status":"documentado"},{"label":"Cota superior absoluta","value":284.75,"unit":"m","source":"EST-SB-20260710 · Estructura A201 / p. 4","status":"documentado"},{"label":"Longitud","value":2,"unit":"m","source":"EST-SB-20260710 · Estructura A201 / p. 4","status":"documentado"},{"label":"Anchura","value":2,"unit":"m","source":"EST-SB-20260710 · Estructura A201 / p. 4","status":"documentado"},{"label":"Canto","value":0.7,"unit":"m","source":"EST-SB-20260710 · Estructura A201 / p. 4","status":"documentado"}],"geometry":[{"label":"Dimensiones de la caja local del elemento (X, Y, Z)","value":"2 × 2 × 0.7","unit":"m","source":"Malla triangulada del elemento en ejes locales del edificio","status":"derivado"},{"label":"Cota mínima absoluta de la malla","value":284.05,"unit":"m","source":"Malla de proyecto y origen altimétrico 285 m","status":"derivado"},{"label":"Cota máxima absoluta de la malla","value":284.75,"unit":"m","source":"Malla de proyecto y origen altimétrico 285 m","status":"derivado"},{"label":"Volumen geométrico bruto","value":2.8,"unit":"m³","source":"Malla cerrada del elemento","status":"derivado"}],"notes":["Las dimensiones documentadas proceden de anotaciones o cuadros; la caja y el volumen se calculan a partir de la malla.","El volumen es exclusivamente geométrico y bruto; no representa una medición neta de material ni una cantidad de compra."]} | {"documentId":"EST-SB-20260710","title":"Planos de estructura de la sala de bombas contra incendios","date":"2026-07-10","sheet":"Estructura A201 / p. 4"} | derivado | ["Profundidad de sustitución o de hormigón ciclópeo bajo zapatas dependiente del terreno real; no modelada sin datos.","Registro de líneas del PDF general con envolvente de 10,2 × 8,2 m. Estimación de trabajo de implantación de ±0,15 m, pendiente de CAD nativo; no constituye una precisión topográfica garantizada."] | {"horizontalStatus":"derivado","verticalStatus":"derivado","baseElevationM":286.25,"note":"Registro de líneas del PDF general con envolvente de 10,2 × 8,2 m. Estimación de trabajo de implantación de ±0,15 m, pendiente de CAD nativo; no constituye una precisión topográfica garantizada."} | {"boundingBoxM":{"min":[7.383617,25.966031,-0.95],"max":[9.637386,28.2198,-0.25]},"extentsM":[2.253769,2.253769,0.7],"meshSurfaceM2":13.599996,"meshVolumeM3":2.799999,"closedSolid":true,"basis":"Geometría triangulada releída del IFC; envolventes y magnitudes no contractuales."} | {"profileId":"concrete_ha30","name":"Hormigón HA-30","materialName":"Hormigón armado HA-30","physicalMaterialStatus":"known","physicalMaterialSource":"EST-SB-20260710 · Estructura A201 / p. 4; nota de resistencia de zapatas y vigas de atado","appearanceStatus":"criterio_visual","appearanceBasis":"Interpretación visual del material documental; el acabado, tono y parámetros PBR no son una especificación contractual.","note":"La apariencia gráfica no modifica ni confirma la especificación física del material."} | {"elementId":"pump_house_0057","ifcGuid":"2fy3ws$jTVqxmQE7P78XMf","ifcClass":"IfcFooting","buildingId":"pump_house","buildingName":"Sala de bombas contra incendios","sourceDocumentId":"EST-SB-20260710","sourceRepresentationKind":"documentary_mesh"} | {"layerId":"foundations","layerName":"Cimentaciones","role":"Zapata aislada","basis":"Clasificación por función del elemento; no modifica las especificaciones documentales."} | {"profileId":"concrete_ha30","name":"Hormigón HA-30","status":"criterio_visual","basis":"Interpretación visual del material documental; el acabado, tono y parámetros PBR no son una especificación contractual.","physicalMaterialUnchanged":true} | 2.8 | Hormigón armado HA-30 | Hormigón HA-30 | pump_house_0057 | EST-SB-20260710 · Estructura A201 / p. 4; nota de resistencia de zapatas y vigas de atado | known | concrete_ha30 | [0.658824,0.658824,0.623529] | 0.94 | Cimentación; BIM · Cimentaciones | Material: Hormigón armado HA-30; JH_DimensionesDelModelo - Dimensiones de la caja local del elemento (X, Y, Z): 2 × 2 × 0.7; Cota mínima absoluta de la malla: 284.05 m; Cota máxima absoluta de la malla: 284.75 m; Volumen geométrico bruto: 2.8 m3; Pset_FootingCommon - Reference: pump_house_0057; Qto_FootingBaseQuantities - GrossVolume: 2.8 m3; JH_InformacionBIM - level: Planta baja; ifcAssociations: {"material":true,"document":true,"quantities":true,"containerGuid":"0Wh59pm9LO_einrwiq6Es1","containerName":"Planta baja"}; JH_Trazabilidad - Planos de referencia: EST-SB-20260710 · Estructura A201 / p. 4; Edificio: Sala de bombas contra incendios; Base geométrica: Dimensiones y cotas documentadas en el cuadro de cimentación.; Sistema de coordenadas: Coordenadas de proyecto en metros; sumar (729400, 4301550, 285) para recuperar las coordenadas UTM y cotas de los planos.; Uso del modelo: Reconstrucción tridimensional de la documentación y revisión preliminar de coordinación; pendiente de revisión por el equipo de diseño.; Hormigón: HA-30; Longitud (m): 2; Anchura (m): 2; Canto (m): 0.7; Cota inferior absoluta (m): 284.05; Cota superior absoluta (m): 284.75; Tratamiento del terreno de apoyo: Profundidad de sustitución o de hormigón ciclópeo bajo zapatas dependiente del terreno real; no modelada sin datos.; Verificación de la malla: Malla cerrada, orientación coherente de las caras y volumen positivo.; Referencia de implantación: Plano general U004 de 2026-07-31; geometría vectorial del PDF registrada con las coordenadas de lindero indicadas.; Estado de la implantación: Registro de líneas del PDF general con envolvente de 10,2 × 8,2 m. Estimación de trabajo de implantación de ±0,15 m, pendiente de CAD nativo; no constituye una precisión topográfica garantizada.; Identificador del elemento: pump_house_0057; Disciplina: Cimentación; Clase IFC: IfcFooting; Fase del modelo: V0.1 · Reconstrucción documental y coordinación preliminar; Representación geométrica: Sólido de malla triangular cerrada en IFC4; Aplicabilidad de las mediciones: Volumen exclusivamente geométrico; los espesores de representación, las simplificaciones y las envolventes no constituyen mediciones de compra, ejecución, fabricación ni volumen neto de material.; Referencia del material: EST-SB-20260710 · Estructura A201 / p. 4; nota de resistencia de zapatas y vigas de atado; Cota de planta baja terminada (m): 286.25; JH_DimensionesDocumentadas - Cota inferior absoluta: 284.05 m; Cota superior absoluta: 284.75 m; Longitud: 2 m; Anchura: 2 m; Canto: 0.7 m
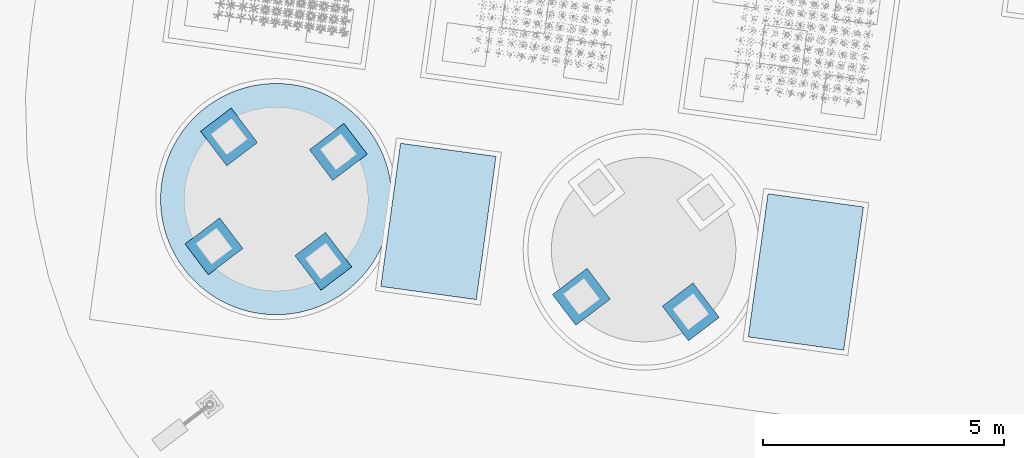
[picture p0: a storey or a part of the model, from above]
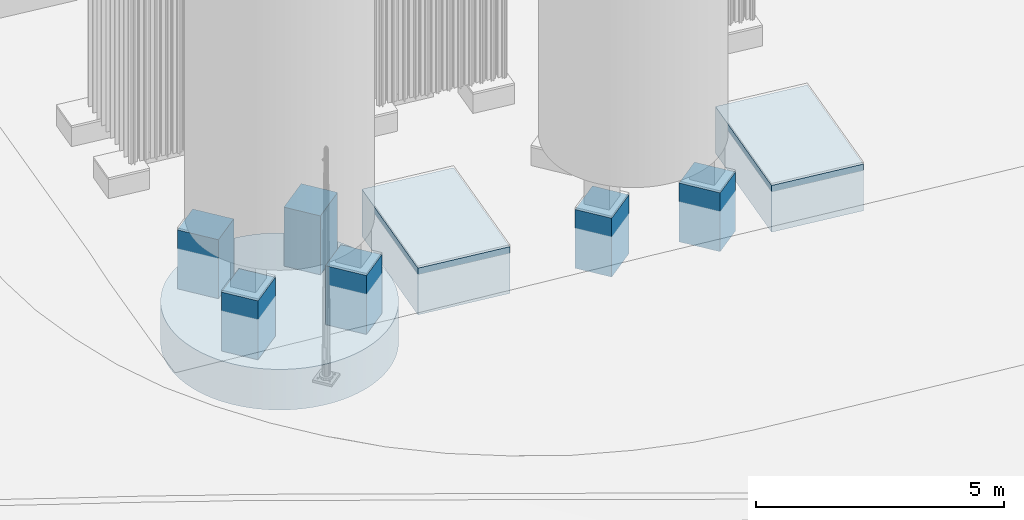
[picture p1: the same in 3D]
Properties of the parts of a building model (IFC4), part 64 of 134

# IfcFooting (214)
Name | In | Description = category = Categoria = Funcion | Document | ExtensionX (m) | ExtensionY (m) | ExtensionZ (m) | SuperficieDeLaMalla (m2) | VolumenGeometrico (m3) | buildingId | buildingName | material | dimensions | JH_InformacionBIM, source = DocumentoFuente | JH_InformacionBIM, status = EstadoDeInformacion | issues = IncidenciasPendientes | positioning = PosicionYEstado | geometryMetrics | materialAppearance | visualizationIdentity | classification | appearance | Volumen geométrico (m³) | JH_Trazabilidad, Material = name | Acabado de visualización = Acabado | Identificador | JH_EvidenciaDeMaterial, source | JH_EvidenciaDeMaterial, status | Perfil | ColorRGB | Rugosidad | Group | Extensión de la malla en X (m) | Extensión de la malla en Y (m) | Extensión de la malla en Z (m) = Espesor o altura real de sección (m) | Cota inferior de visualización (m) | Cota superior de visualización (m) | assemblyId = Conjunto de cimentación | equipmentIds | supportPositionIds | sectionRef = Sección de referencia | sourceCadHandles | stableElementKey | representationKind | geometryStatus | Equipos asociados | Documento de origen | Identificadores CAD de referencia | Cota inferior relativa (m) = Cota inferior relativa adoptada (m) | Cota superior relativa (m) = Cota superior relativa adoptada (m) | Área de planta (m²) | Referencia vertical | Implantación para visualización | Estado de la geometría | Extensión local X (m) | Extensión local Y (m) | Incidencias de origen
Sala de bombas contra incendios · zapata aislada BASE1 · 2 | Planta baja | Zapata aislada | Planos de estructura de la sala de bombas contra incendios | 2.25377 | 2.25377 | 0.7 | 13.6 | 2.8 | pump_house | Sala de bombas contra incendios | {"name":"Hormigón armado HA-30","source":"EST-SB-20260710 · Estructura A201 / p. 4; nota de resistencia de zapatas y vigas de atado","status":"known"} | {"documented":[{"label":"Cota inferior absoluta","value":284.05,"unit":"m","source":"EST-SB-20260710 · Estructura A201 / p. 4","status":"documentado"},{"label":"Cota superior absoluta","value":284.75,"unit":"m","source":"EST-SB-20260710 · Estructura A201 / p. 4","status":"documentado"},{"label":"Longitud","value":2,"unit":"m","source":"EST-SB-20260710 · Estructura A201 / p. 4","status":"documentado"},{"label":"Anchura","value":2,"unit":"m","source":"EST-SB-20260710 · Estructura A201 / p. 4","status":"documentado"},{"label":"Canto","value":0.7,"unit":"m","source":"EST-SB-20260710 · Estructura A201 / p. 4","status":"documentado"}],"geometry":[{"label":"Dimensiones de la caja local del elemento (X, Y, Z)","value":"2 × 2 × 0.7","unit":"m","source":"Malla triangulada del elemento en ejes locales del edificio","status":"derivado"},{"label":"Cota mínima absoluta de la malla","value":284.05,"unit":"m","source":"Malla de proyecto y origen altimétrico 285 m","status":"derivado"},{"label":"Cota máxima absoluta de la malla","value":284.75,"unit":"m","source":"Malla de proyecto y origen altimétrico 285 m","status":"derivado"},{"label":"Volumen geométrico bruto","value":2.8,"unit":"m³","source":"Malla cerrada del elemento","status":"derivado"}],"notes":["Las dimensiones documentadas proceden de anotaciones o cuadros; la caja y el volumen se calculan a partir de la malla.","El volumen es exclusivamente geométrico y bruto; no representa una medición neta de material ni una cantidad de compra."]} | {"documentId":"EST-SB-20260710","title":"Planos de estructura de la sala de bombas contra incendios","date":"2026-07-10","sheet":"Estructura A201 / p. 4"} | derivado | ["Profundidad de sustitución o de hormigón ciclópeo bajo zapatas dependiente del terreno real; no modelada sin datos.","Registro de líneas del PDF general con envolvente de 10,2 × 8,2 m. Estimación de trabajo de implantación de ±0,15 m, pendiente de CAD nativo; no constituye una precisión topográfica garantizada."] | {"horizontalStatus":"derivado","verticalStatus":"derivado","baseElevationM":286.25,"note":"Registro de líneas del PDF general con envolvente de 10,2 × 8,2 m. Estimación de trabajo de implantación de ±0,15 m, pendiente de CAD nativo; no constituye una precisión topográfica garantizada."} | {"boundingBoxM":{"min":[16.795084,24.672094,-0.95],"max":[19.048854,26.925863,-0.25]},"extentsM":[2.25377,2.253769,0.7],"meshSurfaceM2":13.600001,"meshVolumeM3":2.8,"closedSolid":true,"basis":"Geometría triangulada releída del IFC; envolventes y magnitudes no contractuales."} | {"profileId":"concrete_ha30","name":"Hormigón HA-30","materialName":"Hormigón armado HA-30","physicalMaterialStatus":"known","physicalMaterialSource":"EST-SB-20260710 · Estructura A201 / p. 4; nota de resistencia de zapatas y vigas de atado","appearanceStatus":"criterio_visual","appearanceBasis":"Interpretación visual del material documental; el acabado, tono y parámetros PBR no son una especificación contractual.","note":"La apariencia gráfica no modifica ni confirma la especificación física del material."} | {"elementId":"pump_house_0058","ifcGuid":"28fKFrKP1Py9B1dJ7KAQqX","ifcClass":"IfcFooting","buildingId":"pump_house","buildingName":"Sala de bombas contra incendios","sourceDocumentId":"EST-SB-20260710","sourceRepresentationKind":"documentary_mesh"} | {"layerId":"foundations","layerName":"Cimentaciones","role":"Zapata aislada","basis":"Clasificación por función del elemento; no modifica las especificaciones documentales."} | {"profileId":"concrete_ha30","name":"Hormigón HA-30","status":"criterio_visual","basis":"Interpretación visual del material documental; el acabado, tono y parámetros PBR no son una especificación contractual.","physicalMaterialUnchanged":true} | 2.8 | Hormigón armado HA-30 | Hormigón HA-30 | pump_house_0058 | EST-SB-20260710 · Estructura A201 / p. 4; nota de resistencia de zapatas y vigas de atado | known | concrete_ha30 | [0.658824,0.658824,0.623529] | 0.94 | Cimentación; BIM · Cimentaciones | Material: Hormigón armado HA-30; JH_DimensionesDelModelo - Dimensiones de la caja local del elemento (X, Y, Z): 2 × 2 × 0.7; Cota mínima absoluta de la malla: 284.05 m; Cota máxima absoluta de la malla: 284.75 m; Volumen geométrico bruto: 2.8 m3; Pset_FootingCommon - Reference: pump_house_0058; Qto_FootingBaseQuantities - GrossVolume: 2.8 m3; JH_InformacionBIM - level: Planta baja; ifcAssociations: {"material":true,"document":true,"quantities":true,"containerGuid":"0Wh59pm9LO_einrwiq6Es1","containerName":"Planta baja"}; JH_Trazabilidad - Planos de referencia: EST-SB-20260710 · Estructura A201 / p. 4; Edificio: Sala de bombas contra incendios; Base geométrica: Dimensiones y cotas documentadas en el cuadro de cimentación.; Sistema de coordenadas: Coordenadas de proyecto en metros; sumar (729400, 4301550, 285) para recuperar las coordenadas UTM y cotas de los planos.; Uso del modelo: Reconstrucción tridimensional de la documentación y revisión preliminar de coordinación; pendiente de revisión por el equipo de diseño.; Hormigón: HA-30; Longitud (m): 2; Anchura (m): 2; Canto (m): 0.7; Cota inferior absoluta (m): 284.05; Cota superior absoluta (m): 284.75; Tratamiento del terreno de apoyo: Profundidad de sustitución o de hormigón ciclópeo bajo zapatas dependiente del terreno real; no modelada sin datos.; Verificación de la malla: Malla cerrada, orientación coherente de las caras y volumen positivo.; Referencia de implantación: Plano general U004 de 2026-07-31; geometría vectorial del PDF registrada con las coordenadas de lindero indicadas.; Estado de la implantación: Registro de líneas del PDF general con envolvente de 10,2 × 8,2 m. Estimación de trabajo de implantación de ±0,15 m, pendiente de CAD nativo; no constituye una precisión topográfica garantizada.; Identificador del elemento: pump_house_0058; Disciplina: Cimentación; Clase IFC: IfcFooting; Fase del modelo: V0.1 · Reconstrucción documental y coordinación preliminar; Representación geométrica: Sólido de malla triangular cerrada en IFC4; Aplicabilidad de las mediciones: Volumen exclusivamente geométrico; los espesores de representación, las simplificaciones y las envolventes no constituyen mediciones de compra, ejecución, fabricación ni volumen neto de material.; Referencia del material: EST-SB-20260710 · Estructura A201 / p. 4; nota de resistencia de zapatas y vigas de atado; Cota de planta baja terminada (m): 286.25; JH_DimensionesDocumentadas - Cota inferior absoluta: 284.05 m; Cota superior absoluta: 284.75 m; Longitud: 2 m; Anchura: 2 m; Canto: 0.7 m
Sala de bombas contra incendios · zapata aislada BASE1 · 3 | Planta baja | Zapata aislada | Planos de estructura de la sala de bombas contra incendios | 2.25377 | 2.25377 | 0.7 | 13.6 | 2.8 | pump_house | Sala de bombas contra incendios | {"name":"Hormigón armado HA-30","source":"EST-SB-20260710 · Estructura A201 / p. 4; nota de resistencia de zapatas y vigas de atado","status":"known"} | {"documented":[{"label":"Cota inferior absoluta","value":284.05,"unit":"m","source":"EST-SB-20260710 · Estructura A201 / p. 4","status":"documentado"},{"label":"Cota superior absoluta","value":284.75,"unit":"m","source":"EST-SB-20260710 · Estructura A201 / p. 4","status":"documentado"},{"label":"Longitud","value":2,"unit":"m","source":"EST-SB-20260710 · Estructura A201 / p. 4","status":"documentado"},{"label":"Anchura","value":2,"unit":"m","source":"EST-SB-20260710 · Estructura A201 / p. 4","status":"documentado"},{"label":"Canto","value":0.7,"unit":"m","source":"EST-SB-20260710 · Estructura A201 / p. 4","status":"documentado"}],"geometry":[{"label":"Dimensiones de la caja local del elemento (X, Y, Z)","value":"2 × 2 × 0.7","unit":"m","source":"Malla triangulada del elemento en ejes locales del edificio","status":"derivado"},{"label":"Cota mínima absoluta de la malla","value":284.05,"unit":"m","source":"Malla de proyecto y origen altimétrico 285 m","status":"derivado"},{"label":"Cota máxima absoluta de la malla","value":284.75,"unit":"m","source":"Malla de proyecto y origen altimétrico 285 m","status":"derivado"},{"label":"Volumen geométrico bruto","value":2.8,"unit":"m³","source":"Malla cerrada del elemento","status":"derivado"}],"notes":["Las dimensiones documentadas proceden de anotaciones o cuadros; la caja y el volumen se calculan a partir de la malla.","El volumen es exclusivamente geométrico y bruto; no representa una medición neta de material ni una cantidad de compra."]} | {"documentId":"EST-SB-20260710","title":"Planos de estructura de la sala de bombas contra incendios","date":"2026-07-10","sheet":"Estructura A201 / p. 4"} | derivado | ["Profundidad de sustitución o de hormigón ciclópeo bajo zapatas dependiente del terreno real; no modelada sin datos.","Registro de líneas del PDF general con envolvente de 10,2 × 8,2 m. Estimación de trabajo de implantación de ±0,15 m, pendiente de CAD nativo; no constituye una precisión topográfica garantizada."] | {"horizontalStatus":"derivado","verticalStatus":"derivado","baseElevationM":286.25,"note":"Registro de líneas del PDF general con envolvente de 10,2 × 8,2 m. Estimación de trabajo de implantación de ±0,15 m, pendiente de CAD nativo; no constituye una precisión topográfica garantizada."} | {"boundingBoxM":{"min":[8.405146,33.396137,-0.95],"max":[10.658916,35.649906,-0.25]},"extentsM":[2.25377,2.253769,0.7],"meshSurfaceM2":13.600001,"meshVolumeM3":2.8,"closedSolid":true,"basis":"Geometría triangulada releída del IFC; envolventes y magnitudes no contractuales."} | {"profileId":"concrete_ha30","name":"Hormigón HA-30","materialName":"Hormigón armado HA-30","physicalMaterialStatus":"known","physicalMaterialSource":"EST-SB-20260710 · Estructura A201 / p. 4; nota de resistencia de zapatas y vigas de atado","appearanceStatus":"criterio_visual","appearanceBasis":"Interpretación visual del material documental; el acabado, tono y parámetros PBR no son una especificación contractual.","note":"La apariencia gráfica no modifica ni confirma la especificación física del material."} | {"elementId":"pump_house_0059","ifcGuid":"34GqV0$mfPZ96zOyUUY65i","ifcClass":"IfcFooting","buildingId":"pump_house","buildingName":"Sala de bombas contra incendios","sourceDocumentId":"EST-SB-20260710","sourceRepresentationKind":"documentary_mesh"} | {"layerId":"foundations","layerName":"Cimentaciones","role":"Zapata aislada","basis":"Clasificación por función del elemento; no modifica las especificaciones documentales."} | {"profileId":"concrete_ha30","name":"Hormigón HA-30","status":"criterio_visual","basis":"Interpretación visual del material documental; el acabado, tono y parámetros PBR no son una especificación contractual.","physicalMaterialUnchanged":true} | 2.8 | Hormigón armado HA-30 | Hormigón HA-30 | pump_house_0059 | EST-SB-20260710 · Estructura A201 / p. 4; nota de resistencia de zapatas y vigas de atado | known | concrete_ha30 | [0.658824,0.658824,0.623529] | 0.94 | Cimentación; BIM · Cimentaciones | Material: Hormigón armado HA-30; JH_DimensionesDelModelo - Dimensiones de la caja local del elemento (X, Y, Z): 2 × 2 × 0.7; Cota mínima absoluta de la malla: 284.05 m; Cota máxima absoluta de la malla: 284.75 m; Volumen geométrico bruto: 2.8 m3; Pset_FootingCommon - Reference: pump_house_0059; Qto_FootingBaseQuantities - GrossVolume: 2.8 m3; JH_InformacionBIM - level: Planta baja; ifcAssociations: {"material":true,"document":true,"quantities":true,"containerGuid":"0Wh59pm9LO_einrwiq6Es1","containerName":"Planta baja"}; JH_Trazabilidad - Planos de referencia: EST-SB-20260710 · Estructura A201 / p. 4; Edificio: Sala de bombas contra incendios; Base geométrica: Dimensiones y cotas documentadas en el cuadro de cimentación.; Sistema de coordenadas: Coordenadas de proyecto en metros; sumar (729400, 4301550, 285) para recuperar las coordenadas UTM y cotas de los planos.; Uso del modelo: Reconstrucción tridimensional de la documentación y revisión preliminar de coordinación; pendiente de revisión por el equipo de diseño.; Hormigón: HA-30; Longitud (m): 2; Anchura (m): 2; Canto (m): 0.7; Cota inferior absoluta (m): 284.05; Cota superior absoluta (m): 284.75; Tratamiento del terreno de apoyo: Profundidad de sustitución o de hormigón ciclópeo bajo zapatas dependiente del terreno real; no modelada sin datos.; Verificación de la malla: Malla cerrada, orientación coherente de las caras y volumen positivo.; Referencia de implantación: Plano general U004 de 2026-07-31; geometría vectorial del PDF registrada con las coordenadas de lindero indicadas.; Estado de la implantación: Registro de líneas del PDF general con envolvente de 10,2 × 8,2 m. Estimación de trabajo de implantación de ±0,15 m, pendiente de CAD nativo; no constituye una precisión topográfica garantizada.; Identificador del elemento: pump_house_0059; Disciplina: Cimentación; Clase IFC: IfcFooting; Fase del modelo: V0.1 · Reconstrucción documental y coordinación preliminar; Representación geométrica: Sólido de malla triangular cerrada en IFC4; Aplicabilidad de las mediciones: Volumen exclusivamente geométrico; los espesores de representación, las simplificaciones y las envolventes no constituyen mediciones de compra, ejecución, fabricación ni volumen neto de material.; Referencia del material: EST-SB-20260710 · Estructura A201 / p. 4; nota de resistencia de zapatas y vigas de atado; Cota de planta baja terminada (m): 286.25; JH_DimensionesDocumentadas - Cota inferior absoluta: 284.05 m; Cota superior absoluta: 284.75 m; Longitud: 2 m; Anchura: 2 m; Canto: 0.7 m
Sala de bombas contra incendios · zapata aislada BASE1 · 4 | Planta baja | Zapata aislada | Planos de estructura de la sala de bombas contra incendios | 2.25377 | 2.25377 | 0.7 | 13.6 | 2.8 | pump_house | Sala de bombas contra incendios | {"name":"Hormigón armado HA-30","source":"EST-SB-20260710 · Estructura A201 / p. 4; nota de resistencia de zapatas y vigas de atado","status":"known"} | {"documented":[{"label":"Cota inferior absoluta","value":284.05,"unit":"m","source":"EST-SB-20260710 · Estructura A201 / p. 4","status":"documentado"},{"label":"Cota superior absoluta","value":284.75,"unit":"m","source":"EST-SB-20260710 · Estructura A201 / p. 4","status":"documentado"},{"label":"Longitud","value":2,"unit":"m","source":"EST-SB-20260710 · Estructura A201 / p. 4","status":"documentado"},{"label":"Anchura","value":2,"unit":"m","source":"EST-SB-20260710 · Estructura A201 / p. 4","status":"documentado"},{"label":"Canto","value":0.7,"unit":"m","source":"EST-SB-20260710 · Estructura A201 / p. 4","status":"documentado"}],"geometry":[{"label":"Dimensiones de la caja local del elemento (X, Y, Z)","value":"2 × 2 × 0.7","unit":"m","source":"Malla triangulada del elemento en ejes locales del edificio","status":"derivado"},{"label":"Cota mínima absoluta de la malla","value":284.05,"unit":"m","source":"Malla de proyecto y origen altimétrico 285 m","status":"derivado"},{"label":"Cota máxima absoluta de la malla","value":284.75,"unit":"m","source":"Malla de proyecto y origen altimétrico 285 m","status":"derivado"},{"label":"Volumen geométrico bruto","value":2.8,"unit":"m³","source":"Malla cerrada del elemento","status":"derivado"}],"notes":["Las dimensiones documentadas proceden de anotaciones o cuadros; la caja y el volumen se calculan a partir de la malla.","El volumen es exclusivamente geométrico y bruto; no representa una medición neta de material ni una cantidad de compra."]} | {"documentId":"EST-SB-20260710","title":"Planos de estructura de la sala de bombas contra incendios","date":"2026-07-10","sheet":"Estructura A201 / p. 4"} | derivado | ["Profundidad de sustitución o de hormigón ciclópeo bajo zapatas dependiente del terreno real; no modelada sin datos.","Registro de líneas del PDF general con envolvente de 10,2 × 8,2 m. Estimación de trabajo de implantación de ±0,15 m, pendiente de CAD nativo; no constituye una precisión topográfica garantizada."] | {"horizontalStatus":"derivado","verticalStatus":"derivado","baseElevationM":286.25,"note":"Registro de líneas del PDF general con envolvente de 10,2 × 8,2 m. Estimación de trabajo de implantación de ±0,15 m, pendiente de CAD nativo; no constituye una precisión topográfica garantizada."} | {"boundingBoxM":{"min":[17.816614,32.1022,-0.95],"max":[20.070383,34.355969,-0.25]},"extentsM":[2.253769,2.253769,0.7],"meshSurfaceM2":13.599996,"meshVolumeM3":2.799999,"closedSolid":true,"basis":"Geometría triangulada releída del IFC; envolventes y magnitudes no contractuales."} | {"profileId":"concrete_ha30","name":"Hormigón HA-30","materialName":"Hormigón armado HA-30","physicalMaterialStatus":"known","physicalMaterialSource":"EST-SB-20260710 · Estructura A201 / p. 4; nota de resistencia de zapatas y vigas de atado","appearanceStatus":"criterio_visual","appearanceBasis":"Interpretación visual del material documental; el acabado, tono y parámetros PBR no son una especificación contractual.","note":"La apariencia gráfica no modifica ni confirma la especificación física del material."} | {"elementId":"pump_house_0060","ifcGuid":"2xIeLFdJLQwRMiNp10CJnQ","ifcClass":"IfcFooting","buildingId":"pump_house","buildingName":"Sala de bombas contra incendios","sourceDocumentId":"EST-SB-20260710","sourceRepresentationKind":"documentary_mesh"} | {"layerId":"foundations","layerName":"Cimentaciones","role":"Zapata aislada","basis":"Clasificación por función del elemento; no modifica las especificaciones documentales."} | {"profileId":"concrete_ha30","name":"Hormigón HA-30","status":"criterio_visual","basis":"Interpretación visual del material documental; el acabado, tono y parámetros PBR no son una especificación contractual.","physicalMaterialUnchanged":true} | 2.8 | Hormigón armado HA-30 | Hormigón HA-30 | pump_house_0060 | EST-SB-20260710 · Estructura A201 / p. 4; nota de resistencia de zapatas y vigas de atado | known | concrete_ha30 | [0.658824,0.658824,0.623529] | 0.94 | Cimentación; BIM · Cimentaciones | Material: Hormigón armado HA-30; JH_DimensionesDelModelo - Dimensiones de la caja local del elemento (X, Y, Z): 2 × 2 × 0.7; Cota mínima absoluta de la malla: 284.05 m; Cota máxima absoluta de la malla: 284.75 m; Volumen geométrico bruto: 2.8 m3; Pset_FootingCommon - Reference: pump_house_0060; Qto_FootingBaseQuantities - GrossVolume: 2.8 m3; JH_InformacionBIM - level: Planta baja; ifcAssociations: {"material":true,"document":true,"quantities":true,"containerGuid":"0Wh59pm9LO_einrwiq6Es1","containerName":"Planta baja"}; JH_Trazabilidad - Planos de referencia: EST-SB-20260710 · Estructura A201 / p. 4; Edificio: Sala de bombas contra incendios; Base geométrica: Dimensiones y cotas documentadas en el cuadro de cimentación.; Sistema de coordenadas: Coordenadas de proyecto en metros; sumar (729400, 4301550, 285) para recuperar las coordenadas UTM y cotas de los planos.; Uso del modelo: Reconstrucción tridimensional de la documentación y revisión preliminar de coordinación; pendiente de revisión por el equipo de diseño.; Hormigón: HA-30; Longitud (m): 2; Anchura (m): 2; Canto (m): 0.7; Cota inferior absoluta (m): 284.05; Cota superior absoluta (m): 284.75; Tratamiento del terreno de apoyo: Profundidad de sustitución o de hormigón ciclópeo bajo zapatas dependiente del terreno real; no modelada sin datos.; Verificación de la malla: Malla cerrada, orientación coherente de las caras y volumen positivo.; Referencia de implantación: Plano general U004 de 2026-07-31; geometría vectorial del PDF registrada con las coordenadas de lindero indicadas.; Estado de la implantación: Registro de líneas del PDF general con envolvente de 10,2 × 8,2 m. Estimación de trabajo de implantación de ±0,15 m, pendiente de CAD nativo; no constituye una precisión topográfica garantizada.; Identificador del elemento: pump_house_0060; Disciplina: Cimentación; Clase IFC: IfcFooting; Fase del modelo: V0.1 · Reconstrucción documental y coordinación preliminar; Representación geométrica: Sólido de malla triangular cerrada en IFC4; Aplicabilidad de las mediciones: Volumen exclusivamente geométrico; los espesores de representación, las simplificaciones y las envolventes no constituyen mediciones de compra, ejecución, fabricación ni volumen neto de material.; Referencia del material: EST-SB-20260710 · Estructura A201 / p. 4; nota de resistencia de zapatas y vigas de atado; Cota de planta baja terminada (m): 286.25; JH_DimensionesDocumentadas - Cota inferior absoluta: 284.05 m; Cota superior absoluta: 284.75 m; Longitud: 2 m; Anchura: 2 m; Canto: 0.7 m
Edificio de oficinas · zapata aislada BASE1 · 1 | Planta baja | Zapata aislada | Planos de estructura del edificio de oficinas; Planos de estructura del edificio de oficinas | 2.25377 | 2.25377 | 0.7 | 13.6 | 2.8 | office | Edificio de oficinas | {"name":"Hormigón armado HA-30","source":"EST-OF-20260710 · Estructura B201 / p. 5; nota de resistencia de zapatas y vigas de atado","status":"known"} | {"documented":[{"label":"Cota inferior absoluta","value":284.25,"unit":"m","source":"EST-OF-20260710 · Estructura B201 / p. 5","status":"documentado"},{"label":"Cota superior absoluta","value":284.95,"unit":"m","source":"EST-OF-20260710 · Estructura B201 / p. 5","status":"documentado"},{"label":"Longitud","value":2,"unit":"m","source":"EST-OF-20260710 · Estructura B201 / p. 5","status":"documentado"},{"label":"Anchura","value":2,"unit":"m","source":"EST-OF-20260710 · Estructura B201 / p. 5","status":"documentado"},{"label":"Canto","value":0.7,"unit":"m","source":"EST-OF-20260710 · Estructura B201 / p. 5","status":"documentado"}],"geometry":[{"label":"Dimensiones de la caja local del elemento (X, Y, Z)","value":"2 × 2 × 0.7","unit":"m","source":"Malla triangulada del elemento en ejes locales del edificio","status":"derivado"},{"label":"Cota mínima absoluta de la malla","value":284.25,"unit":"m","source":"Malla de proyecto y origen altimétrico 285 m","status":"derivado"},{"label":"Cota máxima absoluta de la malla","value":284.95,"unit":"m","source":"Malla de proyecto y origen altimétrico 285 m","status":"derivado"},{"label":"Volumen geométrico bruto","value":2.8,"unit":"m³","source":"Malla cerrada del elemento","status":"derivado"}],"notes":["Las dimensiones documentadas proceden de anotaciones o cuadros; la caja y el volumen se calculan a partir de la malla.","El volumen es exclusivamente geométrico y bruto; no representa una medición neta de material ni una cantidad de compra."]} | {"documentId":"EST-OF-20260710","title":"Planos de estructura del edificio de oficinas","date":"2026-07-10","sheet":"Estructura B201 / p. 5"} | derivado | ["El plano general de 2026-07-31 mantiene el edificio de oficinas de 200 m², mientras documentación anterior indica su supresión. Se conserva lo dibujado, pendiente de confirmación de la propiedad y del equipo de diseño.","Profundidad de sustitución o de hormigón ciclópeo bajo zapatas dependiente del terreno real; no modelada sin datos.","Registro de líneas del PDF general, envolvente de 20 × 10 m; eje local 1 al norte y acceso del lado A al oeste. Estimación de trabajo de implantación de ±0,15 m, pendiente de CAD; no constituye una precisión topográfica garantizada."] | {"horizontalStatus":"derivado","verticalStatus":"derivado","baseElevationM":285.95,"note":"Registro de líneas del PDF general, envolvente de 20 × 10 m; eje local 1 al norte y acceso del lado A al oeste. Estimación de trabajo de implantación de ±0,15 m, pendiente de CAD; no constituye una precisión topográfica garantizada."} | {"boundingBoxM":{"min":[16.759398,91.390404,-0.75],"max":[19.013167,93.644174,-0.05]},"extentsM":[2.253769,2.25377,0.7],"meshSurfaceM2":13.600001,"meshVolumeM3":2.8,"closedSolid":true,"basis":"Geometría triangulada releída del IFC; envolventes y magnitudes no contractuales."} | {"profileId":"concrete_ha30","name":"Hormigón HA-30","materialName":"Hormigón armado HA-30","physicalMaterialStatus":"known","physicalMaterialSource":"EST-OF-20260710 · Estructura B201 / p. 5; nota de resistencia de zapatas y vigas de atado","appearanceStatus":"criterio_visual","appearanceBasis":"Interpretación visual del material documental; el acabado, tono y parámetros PBR no son una especificación contractual.","note":"La apariencia gráfica no modifica ni confirma la especificación física del material."} | {"elementId":"office_0254","ifcGuid":"2YJyAeiwrOu8c5IIdyuwDO","ifcClass":"IfcFooting","buildingId":"office","buildingName":"Edificio de oficinas","sourceDocumentId":"EST-OF-20260710","sourceRepresentationKind":"documentary_mesh"} | {"layerId":"foundations","layerName":"Cimentaciones","role":"Zapata aislada","basis":"Clasificación por función del elemento; no modifica las especificaciones documentales."} | {"profileId":"concrete_ha30","name":"Hormigón HA-30","status":"criterio_visual","basis":"Interpretación visual del material documental; el acabado, tono y parámetros PBR no son una especificación contractual.","physicalMaterialUnchanged":true} | 2.8 | Hormigón armado HA-30 | Hormigón HA-30 | office_0254 | EST-OF-20260710 · Estructura B201 / p. 5; nota de resistencia de zapatas y vigas de atado | known | concrete_ha30 | [0.658824,0.658824,0.623529] | 0.94 | Cimentación; BIM · Cimentaciones | Material: Hormigón armado HA-30; JH_DimensionesDelModelo - Dimensiones de la caja local del elemento (X, Y, Z): 2 × 2 × 0.7; Cota mínima absoluta de la malla: 284.25 m; Cota máxima absoluta de la malla: 284.95 m; Volumen geométrico bruto: 2.8 m3; Pset_FootingCommon - Reference: office_0254; Qto_FootingBaseQuantities - GrossVolume: 2.8 m3; JH_InformacionBIM - level: Planta baja; ifcAssociations: {"material":true,"document":true,"quantities":true,"containerGuid":"3ztlotcerHPueDgxP84R6z","containerName":"Planta baja"}; JH_Trazabilidad - Planos de referencia: EST-OF-20260710 · Estructura B201 / p. 5; Edificio: Edificio de oficinas; Base geométrica: Dimensiones y cotas documentadas en el cuadro de cimentación.; Sistema de coordenadas: Coordenadas de proyecto en metros; sumar (729400, 4301550, 285) para recuperar las coordenadas UTM y cotas de los planos.; Uso del modelo: Reconstrucción tridimensional de la documentación y revisión preliminar de coordinación; pendiente de revisión por el equipo de diseño.; Hormigón: HA-30; Longitud (m): 2; Anchura (m): 2; Canto (m): 0.7; Cota inferior absoluta (m): 284.25; Cota superior absoluta (m): 284.95; Tratamiento del terreno de apoyo: Profundidad de sustitución o de hormigón ciclópeo bajo zapatas dependiente del terreno real; no modelada sin datos.; Verificación de la malla: Malla cerrada, orientación coherente de las caras y volumen positivo.; Referencia de implantación: Plano general U004 de 2026-07-31; geometría vectorial del PDF registrada con las coordenadas de lindero indicadas.; Estado de la implantación: Registro de líneas del PDF general, envolvente de 20 × 10 m; eje local 1 al norte y acceso del lado A al oeste. Estimación de trabajo de implantación de ±0,15 m, pendiente de CAD; no constituye una precisión topográfica garantizada.; Identificador del elemento: office_0254; Disciplina: Cimentación; Clase IFC: IfcFooting; Fase del modelo: V0.1 · Reconstrucción documental y coordinación preliminar; Representación geométrica: Sólido de malla triangular cerrada en IFC4; Aplicabilidad de las mediciones: Volumen exclusivamente geométrico; los espesores de representación, las simplificaciones y las envolventes no constituyen mediciones de compra, ejecución, fabricación ni volumen neto de material.; Referencia del material: EST-OF-20260710 · Estructura B201 / p. 5; nota de resistencia de zapatas y vigas de atado; Cota de planta baja terminada (m): 285.95; Discrepancia entre versiones: El plano general de 2026-07-31 mantiene el edificio de oficinas de 200 m², mientras documentación anterior indica su supresión. Se conserva lo dibujado, pendiente de confirmación de la propiedad y del equipo de diseño.; JH_DimensionesDocumentadas - Cota inferior absoluta: 284.25 m; Cota superior absoluta: 284.95 m; Longitud: 2 m; Anchura: 2 m; Canto: 0.7 m
Edificio de oficinas · zapata aislada BASE1 · 2 | Planta baja | Zapata aislada | Planos de estructura del edificio de oficinas; Planos de estructura del edificio de oficinas | 2.25377 | 2.25377 | 0.7 | 13.6 | 2.8 | office | Edificio de oficinas | {"name":"Hormigón armado HA-30","source":"EST-OF-20260710 · Estructura B201 / p. 5; nota de resistencia de zapatas y vigas de atado","status":"known"} | {"documented":[{"label":"Cota inferior absoluta","value":284.25,"unit":"m","source":"EST-OF-20260710 · Estructura B201 / p. 5","status":"documentado"},{"label":"Cota superior absoluta","value":284.95,"unit":"m","source":"EST-OF-20260710 · Estructura B201 / p. 5","status":"documentado"},{"label":"Longitud","value":2,"unit":"m","source":"EST-OF-20260710 · Estructura B201 / p. 5","status":"documentado"},{"label":"Anchura","value":2,"unit":"m","source":"EST-OF-20260710 · Estructura B201 / p. 5","status":"documentado"},{"label":"Canto","value":0.7,"unit":"m","source":"EST-OF-20260710 · Estructura B201 / p. 5","status":"documentado"}],"geometry":[{"label":"Dimensiones de la caja local del elemento (X, Y, Z)","value":"2 × 2 × 0.7","unit":"m","source":"Malla triangulada del elemento en ejes locales del edificio","status":"derivado"},{"label":"Cota mínima absoluta de la malla","value":284.25,"unit":"m","source":"Malla de proyecto y origen altimétrico 285 m","status":"derivado"},{"label":"Cota máxima absoluta de la malla","value":284.95,"unit":"m","source":"Malla de proyecto y origen altimétrico 285 m","status":"derivado"},{"label":"Volumen geométrico bruto","value":2.8,"unit":"m³","source":"Malla cerrada del elemento","status":"derivado"}],"notes":["Las dimensiones documentadas proceden de anotaciones o cuadros; la caja y el volumen se calculan a partir de la malla.","El volumen es exclusivamente geométrico y bruto; no representa una medición neta de material ni una cantidad de compra."]} | {"documentId":"EST-OF-20260710","title":"Planos de estructura del edificio de oficinas","date":"2026-07-10","sheet":"Estructura B201 / p. 5"} | derivado | ["El plano general de 2026-07-31 mantiene el edificio de oficinas de 200 m², mientras documentación anterior indica su supresión. Se conserva lo dibujado, pendiente de confirmación de la propiedad y del equipo de diseño.","Profundidad de sustitución o de hormigón ciclópeo bajo zapatas dependiente del terreno real; no modelada sin datos.","Registro de líneas del PDF general, envolvente de 20 × 10 m; eje local 1 al norte y acceso del lado A al oeste. Estimación de trabajo de implantación de ±0,15 m, pendiente de CAD; no constituye una precisión topográfica garantizada."] | {"horizontalStatus":"derivado","verticalStatus":"derivado","baseElevationM":285.95,"note":"Registro de líneas del PDF general, envolvente de 20 × 10 m; eje local 1 al norte y acceso del lado A al oeste. Estimación de trabajo de implantación de ±0,15 m, pendiente de CAD; no constituye una precisión topográfica garantizada."} | {"boundingBoxM":{"min":[15.44503,81.830334,-0.75],"max":[17.6988,84.084104,-0.05]},"extentsM":[2.25377,2.25377,0.7],"meshSurfaceM2":13.600004,"meshVolumeM3":2.800001,"closedSolid":true,"basis":"Geometría triangulada releída del IFC; envolventes y magnitudes no contractuales."} | {"profileId":"concrete_ha30","name":"Hormigón HA-30","materialName":"Hormigón armado HA-30","physicalMaterialStatus":"known","physicalMaterialSource":"EST-OF-20260710 · Estructura B201 / p. 5; nota de resistencia de zapatas y vigas de atado","appearanceStatus":"criterio_visual","appearanceBasis":"Interpretación visual del material documental; el acabado, tono y parámetros PBR no son una especificación contractual.","note":"La apariencia gráfica no modifica ni confirma la especificación física del material."} | {"elementId":"office_0255","ifcGuid":"2CCMTrXwLO6POidscs2ntr","ifcClass":"IfcFooting","buildingId":"office","buildingName":"Edificio de oficinas","sourceDocumentId":"EST-OF-20260710","sourceRepresentationKind":"documentary_mesh"} | {"layerId":"foundations","layerName":"Cimentaciones","role":"Zapata aislada","basis":"Clasificación por función del elemento; no modifica las especificaciones documentales."} | {"profileId":"concrete_ha30","name":"Hormigón HA-30","status":"criterio_visual","basis":"Interpretación visual del material documental; el acabado, tono y parámetros PBR no son una especificación contractual.","physicalMaterialUnchanged":true} | 2.8 | Hormigón armado HA-30 | Hormigón HA-30 | office_0255 | EST-OF-20260710 · Estructura B201 / p. 5; nota de resistencia de zapatas y vigas de atado | known | concrete_ha30 | [0.658824,0.658824,0.623529] | 0.94 | Cimentación; BIM · Cimentaciones | Material: Hormigón armado HA-30; JH_DimensionesDelModelo - Dimensiones de la caja local del elemento (X, Y, Z): 2 × 2 × 0.7; Cota mínima absoluta de la malla: 284.25 m; Cota máxima absoluta de la malla: 284.95 m; Volumen geométrico bruto: 2.8 m3; Pset_FootingCommon - Reference: office_0255; Qto_FootingBaseQuantities - GrossVolume: 2.8 m3; JH_InformacionBIM - level: Planta baja; ifcAssociations: {"material":true,"document":true,"quantities":true,"containerGuid":"3ztlotcerHPueDgxP84R6z","containerName":"Planta baja"}; JH_Trazabilidad - Planos de referencia: EST-OF-20260710 · Estructura B201 / p. 5; Edificio: Edificio de oficinas; Base geométrica: Dimensiones y cotas documentadas en el cuadro de cimentación.; Sistema de coordenadas: Coordenadas de proyecto en metros; sumar (729400, 4301550, 285) para recuperar las coordenadas UTM y cotas de los planos.; Uso del modelo: Reconstrucción tridimensional de la documentación y revisión preliminar de coordinación; pendiente de revisión por el equipo de diseño.; Hormigón: HA-30; Longitud (m): 2; Anchura (m): 2; Canto (m): 0.7; Cota inferior absoluta (m): 284.25; Cota superior absoluta (m): 284.95; Tratamiento del terreno de apoyo: Profundidad de sustitución o de hormigón ciclópeo bajo zapatas dependiente del terreno real; no modelada sin datos.; Verificación de la malla: Malla cerrada, orientación coherente de las caras y volumen positivo.; Referencia de implantación: Plano general U004 de 2026-07-31; geometría vectorial del PDF registrada con las coordenadas de lindero indicadas.; Estado de la implantación: Registro de líneas del PDF general, envolvente de 20 × 10 m; eje local 1 al norte y acceso del lado A al oeste. Estimación de trabajo de implantación de ±0,15 m, pendiente de CAD; no constituye una precisión topográfica garantizada.; Identificador del elemento: office_0255; Disciplina: Cimentación; Clase IFC: IfcFooting; Fase del modelo: V0.1 · Reconstrucción documental y coordinación preliminar; Representación geométrica: Sólido de malla triangular cerrada en IFC4; Aplicabilidad de las mediciones: Volumen exclusivamente geométrico; los espesores de representación, las simplificaciones y las envolventes no constituyen mediciones de compra, ejecución, fabricación ni volumen neto de material.; Referencia del material: EST-OF-20260710 · Estructura B201 / p. 5; nota de resistencia de zapatas y vigas de atado; Cota de planta baja terminada (m): 285.95; Discrepancia entre versiones: El plano general de 2026-07-31 mantiene el edificio de oficinas de 200 m², mientras documentación anterior indica su supresión. Se conserva lo dibujado, pendiente de confirmación de la propiedad y del equipo de diseño.; JH_DimensionesDocumentadas - Cota inferior absoluta: 284.25 m; Cota superior absoluta: 284.95 m; Longitud: 2 m; Anchura: 2 m; Canto: 0.7 m
Edificio de oficinas · zapata aislada BASE1 · 3 | Planta baja | Zapata aislada | Planos de estructura del edificio de oficinas; Planos de estructura del edificio de oficinas | 2.25377 | 2.25377 | 0.7 | 13.6 | 2.8 | office | Edificio de oficinas | {"name":"Hormigón armado HA-30","source":"EST-OF-20260710 · Estructura B201 / p. 5; nota de resistencia de zapatas y vigas de atado","status":"known"} | {"documented":[{"label":"Cota inferior absoluta","value":284.25,"unit":"m","source":"EST-OF-20260710 · Estructura B201 / p. 5","status":"documentado"},{"label":"Cota superior absoluta","value":284.95,"unit":"m","source":"EST-OF-20260710 · Estructura B201 / p. 5","status":"documentado"},{"label":"Longitud","value":2,"unit":"m","source":"EST-OF-20260710 · Estructura B201 / p. 5","status":"documentado"},{"label":"Anchura","value":2,"unit":"m","source":"EST-OF-20260710 · Estructura B201 / p. 5","status":"documentado"},{"label":"Canto","value":0.7,"unit":"m","source":"EST-OF-20260710 · Estructura B201 / p. 5","status":"documentado"}],"geometry":[{"label":"Dimensiones de la caja local del elemento (X, Y, Z)","value":"2 × 2 × 0.7","unit":"m","source":"Malla triangulada del elemento en ejes locales del edificio","status":"derivado"},{"label":"Cota mínima absoluta de la malla","value":284.25,"unit":"m","source":"Malla de proyecto y origen altimétrico 285 m","status":"derivado"},{"label":"Cota máxima absoluta de la malla","value":284.95,"unit":"m","source":"Malla de proyecto y origen altimétrico 285 m","status":"derivado"},{"label":"Volumen geométrico bruto","value":2.8,"unit":"m³","source":"Malla cerrada del elemento","status":"derivado"}],"notes":["Las dimensiones documentadas proceden de anotaciones o cuadros; la caja y el volumen se calculan a partir de la malla.","El volumen es exclusivamente geométrico y bruto; no representa una medición neta de material ni una cantidad de compra."]} | {"documentId":"EST-OF-20260710","title":"Planos de estructura del edificio de oficinas","date":"2026-07-10","sheet":"Estructura B201 / p. 5"} | derivado | ["El plano general de 2026-07-31 mantiene el edificio de oficinas de 200 m², mientras documentación anterior indica su supresión. Se conserva lo dibujado, pendiente de confirmación de la propiedad y del equipo de diseño.","Profundidad de sustitución o de hormigón ciclópeo bajo zapatas dependiente del terreno real; no modelada sin datos.","Registro de líneas del PDF general, envolvente de 20 × 10 m; eje local 1 al norte y acceso del lado A al oeste. Estimación de trabajo de implantación de ±0,15 m, pendiente de CAD; no constituye una precisión topográfica garantizada."] | {"horizontalStatus":"derivado","verticalStatus":"derivado","baseElevationM":285.95,"note":"Registro de líneas del PDF general, envolvente de 20 × 10 m; eje local 1 al norte y acceso del lado A al oeste. Estimación de trabajo de implantación de ±0,15 m, pendiente de CAD; no constituye una precisión topográfica garantizada."} | {"boundingBoxM":{"min":[14.130662,72.270264,-0.75],"max":[16.384432,74.524034,-0.05]},"extentsM":[2.25377,2.25377,0.7],"meshSurfaceM2":13.600004,"meshVolumeM3":2.800001,"closedSolid":true,"basis":"Geometría triangulada releída del IFC; envolventes y magnitudes no contractuales."} | {"profileId":"concrete_ha30","name":"Hormigón HA-30","materialName":"Hormigón armado HA-30","physicalMaterialStatus":"known","physicalMaterialSource":"EST-OF-20260710 · Estructura B201 / p. 5; nota de resistencia de zapatas y vigas de atado","appearanceStatus":"criterio_visual","appearanceBasis":"Interpretación visual del material documental; el acabado, tono y parámetros PBR no son una especificación contractual.","note":"La apariencia gráfica no modifica ni confirma la especificación física del material."} | {"elementId":"office_0256","ifcGuid":"3$jMfwdc1KoOgkuhyfb2Zv","ifcClass":"IfcFooting","buildingId":"office","buildingName":"Edificio de oficinas","sourceDocumentId":"EST-OF-20260710","sourceRepresentationKind":"documentary_mesh"} | {"layerId":"foundations","layerName":"Cimentaciones","role":"Zapata aislada","basis":"Clasificación por función del elemento; no modifica las especificaciones documentales."} | {"profileId":"concrete_ha30","name":"Hormigón HA-30","status":"criterio_visual","basis":"Interpretación visual del material documental; el acabado, tono y parámetros PBR no son una especificación contractual.","physicalMaterialUnchanged":true} | 2.8 | Hormigón armado HA-30 | Hormigón HA-30 | office_0256 | EST-OF-20260710 · Estructura B201 / p. 5; nota de resistencia de zapatas y vigas de atado | known | concrete_ha30 | [0.658824,0.658824,0.623529] | 0.94 | Cimentación; BIM · Cimentaciones | Material: Hormigón armado HA-30; JH_DimensionesDelModelo - Dimensiones de la caja local del elemento (X, Y, Z): 2 × 2 × 0.7; Cota mínima absoluta de la malla: 284.25 m; Cota máxima absoluta de la malla: 284.95 m; Volumen geométrico bruto: 2.8 m3; Pset_FootingCommon - Reference: office_0256; Qto_FootingBaseQuantities - GrossVolume: 2.8 m3; JH_InformacionBIM - level: Planta baja; ifcAssociations: {"material":true,"document":true,"quantities":true,"containerGuid":"3ztlotcerHPueDgxP84R6z","containerName":"Planta baja"}; JH_Trazabilidad - Planos de referencia: EST-OF-20260710 · Estructura B201 / p. 5; Edificio: Edificio de oficinas; Base geométrica: Dimensiones y cotas documentadas en el cuadro de cimentación.; Sistema de coordenadas: Coordenadas de proyecto en metros; sumar (729400, 4301550, 285) para recuperar las coordenadas UTM y cotas de los planos.; Uso del modelo: Reconstrucción tridimensional de la documentación y revisión preliminar de coordinación; pendiente de revisión por el equipo de diseño.; Hormigón: HA-30; Longitud (m): 2; Anchura (m): 2; Canto (m): 0.7; Cota inferior absoluta (m): 284.25; Cota superior absoluta (m): 284.95; Tratamiento del terreno de apoyo: Profundidad de sustitución o de hormigón ciclópeo bajo zapatas dependiente del terreno real; no modelada sin datos.; Verificación de la malla: Malla cerrada, orientación coherente de las caras y volumen positivo.; Referencia de implantación: Plano general U004 de 2026-07-31; geometría vectorial del PDF registrada con las coordenadas de lindero indicadas.; Estado de la implantación: Registro de líneas del PDF general, envolvente de 20 × 10 m; eje local 1 al norte y acceso del lado A al oeste. Estimación de trabajo de implantación de ±0,15 m, pendiente de CAD; no constituye una precisión topográfica garantizada.; Identificador del elemento: office_0256; Disciplina: Cimentación; Clase IFC: IfcFooting; Fase del modelo: V0.1 · Reconstrucción documental y coordinación preliminar; Representación geométrica: Sólido de malla triangular cerrada en IFC4; Aplicabilidad de las mediciones: Volumen exclusivamente geométrico; los espesores de representación, las simplificaciones y las envolventes no constituyen mediciones de compra, ejecución, fabricación ni volumen neto de material.; Referencia del material: EST-OF-20260710 · Estructura B201 / p. 5; nota de resistencia de zapatas y vigas de atado; Cota de planta baja terminada (m): 285.95; Discrepancia entre versiones: El plano general de 2026-07-31 mantiene el edificio de oficinas de 200 m², mientras documentación anterior indica su supresión. Se conserva lo dibujado, pendiente de confirmación de la propiedad y del equipo de diseño.; JH_DimensionesDocumentadas - Cota inferior absoluta: 284.25 m; Cota superior absoluta: 284.95 m; Longitud: 2 m; Anchura: 2 m; Canto: 0.7 m
Edificio de oficinas · zapata aislada BASE1 · 4 | Planta baja | Zapata aislada | Planos de estructura del edificio de oficinas; Planos de estructura del edificio de oficinas | 2.25377 | 2.25377 | 0.7 | 13.6 | 2.8 | office | Edificio de oficinas | {"name":"Hormigón armado HA-30","source":"EST-OF-20260710 · Estructura B201 / p. 5; nota de resistencia de zapatas y vigas de atado","status":"known"} | {"documented":[{"label":"Cota inferior absoluta","value":284.25,"unit":"m","source":"EST-OF-20260710 · Estructura B201 / p. 5","status":"documentado"},{"label":"Cota superior absoluta","value":284.95,"unit":"m","source":"EST-OF-20260710 · Estructura B201 / p. 5","status":"documentado"},{"label":"Longitud","value":2,"unit":"m","source":"EST-OF-20260710 · Estructura B201 / p. 5","status":"documentado"},{"label":"Anchura","value":2,"unit":"m","source":"EST-OF-20260710 · Estructura B201 / p. 5","status":"documentado"},{"label":"Canto","value":0.7,"unit":"m","source":"EST-OF-20260710 · Estructura B201 / p. 5","status":"documentado"}],"geometry":[{"label":"Dimensiones de la caja local del elemento (X, Y, Z)","value":"2 × 2 × 0.7","unit":"m","source":"Malla triangulada del elemento en ejes locales del edificio","status":"derivado"},{"label":"Cota mínima absoluta de la malla","value":284.25,"unit":"m","source":"Malla de proyecto y origen altimétrico 285 m","status":"derivado"},{"label":"Cota máxima absoluta de la malla","value":284.95,"unit":"m","source":"Malla de proyecto y origen altimétrico 285 m","status":"derivado"},{"label":"Volumen geométrico bruto","value":2.8,"unit":"m³","source":"Malla cerrada del elemento","status":"derivado"}],"notes":["Las dimensiones documentadas proceden de anotaciones o cuadros; la caja y el volumen se calculan a partir de la malla.","El volumen es exclusivamente geométrico y bruto; no representa una medición neta de material ni una cantidad de compra."]} | {"documentId":"EST-OF-20260710","title":"Planos de estructura del edificio de oficinas","date":"2026-07-10","sheet":"Estructura B201 / p. 5"} | derivado | ["El plano general de 2026-07-31 mantiene el edificio de oficinas de 200 m², mientras documentación anterior indica su supresión. Se conserva lo dibujado, pendiente de confirmación de la propiedad y del equipo de diseño.","Profundidad de sustitución o de hormigón ciclópeo bajo zapatas dependiente del terreno real; no modelada sin datos.","Registro de líneas del PDF general, envolvente de 20 × 10 m; eje local 1 al norte y acceso del lado A al oeste. Estimación de trabajo de implantación de ±0,15 m, pendiente de CAD; no constituye una precisión topográfica garantizada."] | {"horizontalStatus":"derivado","verticalStatus":"derivado","baseElevationM":285.95,"note":"Registro de líneas del PDF general, envolvente de 20 × 10 m; eje local 1 al norte y acceso del lado A al oeste. Estimación de trabajo de implantación de ±0,15 m, pendiente de CAD; no constituye una precisión topográfica garantizada."} | {"boundingBoxM":{"min":[25.883568,90.135966,-0.75],"max":[28.137338,92.389736,-0.05]},"extentsM":[2.25377,2.25377,0.7],"meshSurfaceM2":13.600004,"meshVolumeM3":2.800001,"closedSolid":true,"basis":"Geometría triangulada releída del IFC; envolventes y magnitudes no contractuales."} | {"profileId":"concrete_ha30","name":"Hormigón HA-30","materialName":"Hormigón armado HA-30","physicalMaterialStatus":"known","physicalMaterialSource":"EST-OF-20260710 · Estructura B201 / p. 5; nota de resistencia de zapatas y vigas de atado","appearanceStatus":"criterio_visual","appearanceBasis":"Interpretación visual del material documental; el acabado, tono y parámetros PBR no son una especificación contractual.","note":"La apariencia gráfica no modifica ni confirma la especificación física del material."} | {"elementId":"office_0257","ifcGuid":"1YxtP2e8rNtxMnVSb$xKXw","ifcClass":"IfcFooting","buildingId":"office","buildingName":"Edificio de oficinas","sourceDocumentId":"EST-OF-20260710","sourceRepresentationKind":"documentary_mesh"} | {"layerId":"foundations","layerName":"Cimentaciones","role":"Zapata aislada","basis":"Clasificación por función del elemento; no modifica las especificaciones documentales."} | {"profileId":"concrete_ha30","name":"Hormigón HA-30","status":"criterio_visual","basis":"Interpretación visual del material documental; el acabado, tono y parámetros PBR no son una especificación contractual.","physicalMaterialUnchanged":true} | 2.8 | Hormigón armado HA-30 | Hormigón HA-30 | office_0257 | EST-OF-20260710 · Estructura B201 / p. 5; nota de resistencia de zapatas y vigas de atado | known | concrete_ha30 | [0.658824,0.658824,0.623529] | 0.94 | Cimentación; BIM · Cimentaciones | Material: Hormigón armado HA-30; JH_DimensionesDelModelo - Dimensiones de la caja local del elemento (X, Y, Z): 2 × 2 × 0.7; Cota mínima absoluta de la malla: 284.25 m; Cota máxima absoluta de la malla: 284.95 m; Volumen geométrico bruto: 2.8 m3; Pset_FootingCommon - Reference: office_0257; Qto_FootingBaseQuantities - GrossVolume: 2.8 m3; JH_InformacionBIM - level: Planta baja; ifcAssociations: {"material":true,"document":true,"quantities":true,"containerGuid":"3ztlotcerHPueDgxP84R6z","containerName":"Planta baja"}; JH_Trazabilidad - Planos de referencia: EST-OF-20260710 · Estructura B201 / p. 5; Edificio: Edificio de oficinas; Base geométrica: Dimensiones y cotas documentadas en el cuadro de cimentación.; Sistema de coordenadas: Coordenadas de proyecto en metros; sumar (729400, 4301550, 285) para recuperar las coordenadas UTM y cotas de los planos.; Uso del modelo: Reconstrucción tridimensional de la documentación y revisión preliminar de coordinación; pendiente de revisión por el equipo de diseño.; Hormigón: HA-30; Longitud (m): 2; Anchura (m): 2; Canto (m): 0.7; Cota inferior absoluta (m): 284.25; Cota superior absoluta (m): 284.95; Tratamiento del terreno de apoyo: Profundidad de sustitución o de hormigón ciclópeo bajo zapatas dependiente del terreno real; no modelada sin datos.; Verificación de la malla: Malla cerrada, orientación coherente de las caras y volumen positivo.; Referencia de implantación: Plano general U004 de 2026-07-31; geometría vectorial del PDF registrada con las coordenadas de lindero indicadas.; Estado de la implantación: Registro de líneas del PDF general, envolvente de 20 × 10 m; eje local 1 al norte y acceso del lado A al oeste. Estimación de trabajo de implantación de ±0,15 m, pendiente de CAD; no constituye una precisión topográfica garantizada.; Identificador del elemento: office_0257; Disciplina: Cimentación; Clase IFC: IfcFooting; Fase del modelo: V0.1 · Reconstrucción documental y coordinación preliminar; Representación geométrica: Sólido de malla triangular cerrada en IFC4; Aplicabilidad de las mediciones: Volumen exclusivamente geométrico; los espesores de representación, las simplificaciones y las envolventes no constituyen mediciones de compra, ejecución, fabricación ni volumen neto de material.; Referencia del material: EST-OF-20260710 · Estructura B201 / p. 5; nota de resistencia de zapatas y vigas de atado; Cota de planta baja terminada (m): 285.95; Discrepancia entre versiones: El plano general de 2026-07-31 mantiene el edificio de oficinas de 200 m², mientras documentación anterior indica su supresión. Se conserva lo dibujado, pendiente de confirmación de la propiedad y del equipo de diseño.; JH_DimensionesDocumentadas - Cota inferior absoluta: 284.25 m; Cota superior absoluta: 284.95 m; Longitud: 2 m; Anchura: 2 m; Canto: 0.7 m
Edificio de oficinas · zapata aislada BASE1 · 5 | Planta baja | Zapata aislada | Planos de estructura del edificio de oficinas; Planos de estructura del edificio de oficinas | 2.25377 | 2.25377 | 0.7 | 13.6 | 2.8 | office | Edificio de oficinas | {"name":"Hormigón armado HA-30","source":"EST-OF-20260710 · Estructura B201 / p. 5; nota de resistencia de zapatas y vigas de atado","status":"known"} | {"documented":[{"label":"Cota inferior absoluta","value":284.25,"unit":"m","source":"EST-OF-20260710 · Estructura B201 / p. 5","status":"documentado"},{"label":"Cota superior absoluta","value":284.95,"unit":"m","source":"EST-OF-20260710 · Estructura B201 / p. 5","status":"documentado"},{"label":"Longitud","value":2,"unit":"m","source":"EST-OF-20260710 · Estructura B201 / p. 5","status":"documentado"},{"label":"Anchura","value":2,"unit":"m","source":"EST-OF-20260710 · Estructura B201 / p. 5","status":"documentado"},{"label":"Canto","value":0.7,"unit":"m","source":"EST-OF-20260710 · Estructura B201 / p. 5","status":"documentado"}],"geometry":[{"label":"Dimensiones de la caja local del elemento (X, Y, Z)","value":"2 × 2 × 0.7","unit":"m","source":"Malla triangulada del elemento en ejes locales del edificio","status":"derivado"},{"label":"Cota mínima absoluta de la malla","value":284.25,"unit":"m","source":"Malla de proyecto y origen altimétrico 285 m","status":"derivado"},{"label":"Cota máxima absoluta de la malla","value":284.95,"unit":"m","source":"Malla de proyecto y origen altimétrico 285 m","status":"derivado"},{"label":"Volumen geométrico bruto","value":2.8,"unit":"m³","source":"Malla cerrada del elemento","status":"derivado"}],"notes":["Las dimensiones documentadas proceden de anotaciones o cuadros; la caja y el volumen se calculan a partir de la malla.","El volumen es exclusivamente geométrico y bruto; no representa una medición neta de material ni una cantidad de compra."]} | {"documentId":"EST-OF-20260710","title":"Planos de estructura del edificio de oficinas","date":"2026-07-10","sheet":"Estructura B201 / p. 5"} | derivado | ["El plano general de 2026-07-31 mantiene el edificio de oficinas de 200 m², mientras documentación anterior indica su supresión. Se conserva lo dibujado, pendiente de confirmación de la propiedad y del equipo de diseño.","Profundidad de sustitución o de hormigón ciclópeo bajo zapatas dependiente del terreno real; no modelada sin datos.","Registro de líneas del PDF general, envolvente de 20 × 10 m; eje local 1 al norte y acceso del lado A al oeste. Estimación de trabajo de implantación de ±0,15 m, pendiente de CAD; no constituye una precisión topográfica garantizada."] | {"horizontalStatus":"derivado","verticalStatus":"derivado","baseElevationM":285.95,"note":"Registro de líneas del PDF general, envolvente de 20 × 10 m; eje local 1 al norte y acceso del lado A al oeste. Estimación de trabajo de implantación de ±0,15 m, pendiente de CAD; no constituye una precisión topográfica garantizada."} | {"boundingBoxM":{"min":[24.5692,80.575896,-0.75],"max":[26.82297,82.829666,-0.05]},"extentsM":[2.25377,2.25377,0.7],"meshSurfaceM2":13.600004,"meshVolumeM3":2.800001,"closedSolid":true,"basis":"Geometría triangulada releída del IFC; envolventes y magnitudes no contractuales."} | {"profileId":"concrete_ha30","name":"Hormigón HA-30","materialName":"Hormigón armado HA-30","physicalMaterialStatus":"known","physicalMaterialSource":"EST-OF-20260710 · Estructura B201 / p. 5; nota de resistencia de zapatas y vigas de atado","appearanceStatus":"criterio_visual","appearanceBasis":"Interpretación visual del material documental; el acabado, tono y parámetros PBR no son una especificación contractual.","note":"La apariencia gráfica no modifica ni confirma la especificación física del material."} | {"elementId":"office_0258","ifcGuid":"3Vfc33WCfK7eJISZAITmxh","ifcClass":"IfcFooting","buildingId":"office","buildingName":"Edificio de oficinas","sourceDocumentId":"EST-OF-20260710","sourceRepresentationKind":"documentary_mesh"} | {"layerId":"foundations","layerName":"Cimentaciones","role":"Zapata aislada","basis":"Clasificación por función del elemento; no modifica las especificaciones documentales."} | {"profileId":"concrete_ha30","name":"Hormigón HA-30","status":"criterio_visual","basis":"Interpretación visual del material documental; el acabado, tono y parámetros PBR no son una especificación contractual.","physicalMaterialUnchanged":true} | 2.8 | Hormigón armado HA-30 | Hormigón HA-30 | office_0258 | EST-OF-20260710 · Estructura B201 / p. 5; nota de resistencia de zapatas y vigas de atado | known | concrete_ha30 | [0.658824,0.658824,0.623529] | 0.94 | Cimentación; BIM · Cimentaciones | Material: Hormigón armado HA-30; JH_DimensionesDelModelo - Dimensiones de la caja local del elemento (X, Y, Z): 2 × 2 × 0.7; Cota mínima absoluta de la malla: 284.25 m; Cota máxima absoluta de la malla: 284.95 m; Volumen geométrico bruto: 2.8 m3; Pset_FootingCommon - Reference: office_0258; Qto_FootingBaseQuantities - GrossVolume: 2.8 m3; JH_InformacionBIM - level: Planta baja; ifcAssociations: {"material":true,"document":true,"quantities":true,"containerGuid":"3ztlotcerHPueDgxP84R6z","containerName":"Planta baja"}; JH_Trazabilidad - Planos de referencia: EST-OF-20260710 · Estructura B201 / p. 5; Edificio: Edificio de oficinas; Base geométrica: Dimensiones y cotas documentadas en el cuadro de cimentación.; Sistema de coordenadas: Coordenadas de proyecto en metros; sumar (729400, 4301550, 285) para recuperar las coordenadas UTM y cotas de los planos.; Uso del modelo: Reconstrucción tridimensional de la documentación y revisión preliminar de coordinación; pendiente de revisión por el equipo de diseño.; Hormigón: HA-30; Longitud (m): 2; Anchura (m): 2; Canto (m): 0.7; Cota inferior absoluta (m): 284.25; Cota superior absoluta (m): 284.95; Tratamiento del terreno de apoyo: Profundidad de sustitución o de hormigón ciclópeo bajo zapatas dependiente del terreno real; no modelada sin datos.; Verificación de la malla: Malla cerrada, orientación coherente de las caras y volumen positivo.; Referencia de implantación: Plano general U004 de 2026-07-31; geometría vectorial del PDF registrada con las coordenadas de lindero indicadas.; Estado de la implantación: Registro de líneas del PDF general, envolvente de 20 × 10 m; eje local 1 al norte y acceso del lado A al oeste. Estimación de trabajo de implantación de ±0,15 m, pendiente de CAD; no constituye una precisión topográfica garantizada.; Identificador del elemento: office_0258; Disciplina: Cimentación; Clase IFC: IfcFooting; Fase del modelo: V0.1 · Reconstrucción documental y coordinación preliminar; Representación geométrica: Sólido de malla triangular cerrada en IFC4; Aplicabilidad de las mediciones: Volumen exclusivamente geométrico; los espesores de representación, las simplificaciones y las envolventes no constituyen mediciones de compra, ejecución, fabricación ni volumen neto de material.; Referencia del material: EST-OF-20260710 · Estructura B201 / p. 5; nota de resistencia de zapatas y vigas de atado; Cota de planta baja terminada (m): 285.95; Discrepancia entre versiones: El plano general de 2026-07-31 mantiene el edificio de oficinas de 200 m², mientras documentación anterior indica su supresión. Se conserva lo dibujado, pendiente de confirmación de la propiedad y del equipo de diseño.; JH_DimensionesDocumentadas - Cota inferior absoluta: 284.25 m; Cota superior absoluta: 284.95 m; Longitud: 2 m; Anchura: 2 m; Canto: 0.7 m
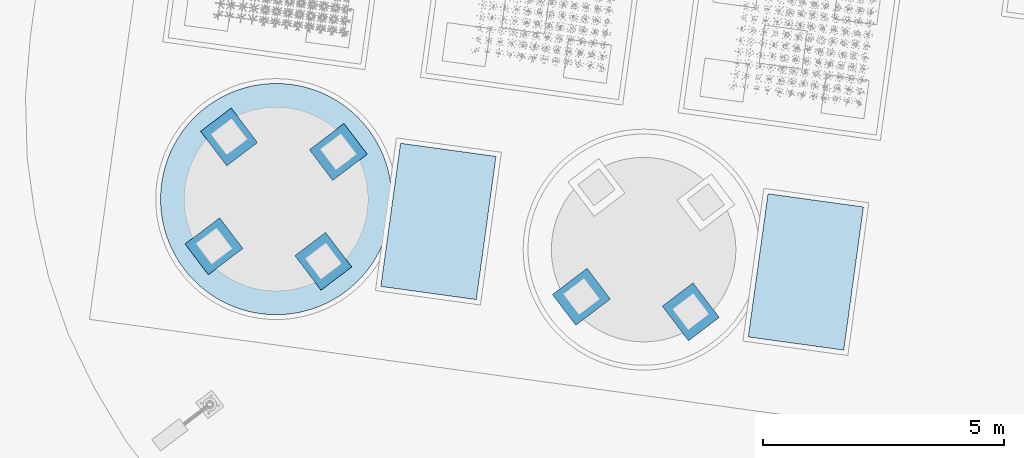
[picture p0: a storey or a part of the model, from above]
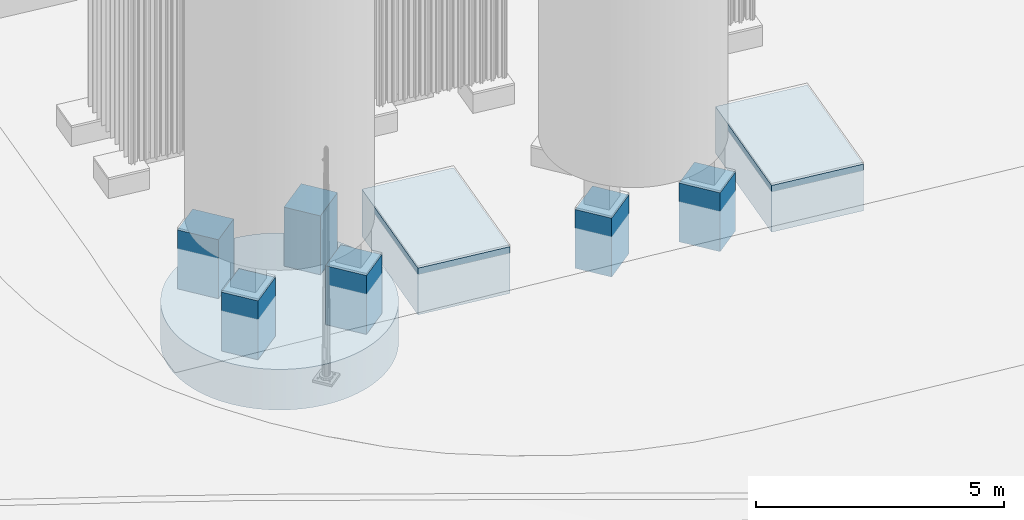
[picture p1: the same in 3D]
Properties of the parts of a building model (IFC4), part 65 of 134

# IfcFooting (214)
Name | In | Description = category = Categoria = Funcion | Document | ExtensionX (m) | ExtensionY (m) | ExtensionZ (m) | SuperficieDeLaMalla (m2) | VolumenGeometrico (m3) | buildingId | buildingName | material | dimensions | JH_InformacionBIM, source = DocumentoFuente | JH_InformacionBIM, status = EstadoDeInformacion | issues = IncidenciasPendientes | positioning = PosicionYEstado | geometryMetrics | materialAppearance | visualizationIdentity | classification | appearance | Volumen geométrico (m³) | JH_Trazabilidad, Material = name | Acabado de visualización = Acabado | Identificador | JH_EvidenciaDeMaterial, source | JH_EvidenciaDeMaterial, status | Perfil | ColorRGB | Rugosidad | Group | Extensión de la malla en X (m) | Extensión de la malla en Y (m) | Extensión de la malla en Z (m) = Espesor o altura real de sección (m) | Cota inferior de visualización (m) | Cota superior de visualización (m) | assemblyId = Conjunto de cimentación | equipmentIds | supportPositionIds | sectionRef = Sección de referencia | sourceCadHandles | stableElementKey | representationKind | geometryStatus | Equipos asociados | Documento de origen | Identificadores CAD de referencia | Cota inferior relativa (m) = Cota inferior relativa adoptada (m) | Cota superior relativa (m) = Cota superior relativa adoptada (m) | Área de planta (m²) | Referencia vertical | Implantación para visualización | Estado de la geometría | Extensión local X (m) | Extensión local Y (m) | Incidencias de origen
Edificio de oficinas · zapata aislada BASE1 · 6 | Planta baja | Zapata aislada | Planos de estructura del edificio de oficinas; Planos de estructura del edificio de oficinas | 2.25377 | 2.25377 | 0.7 | 13.6 | 2.8 | office | Edificio de oficinas | {"name":"Hormigón armado HA-30","source":"EST-OF-20260710 · Estructura B201 / p. 5; nota de resistencia de zapatas y vigas de atado","status":"known"} | {"documented":[{"label":"Cota inferior absoluta","value":284.25,"unit":"m","source":"EST-OF-20260710 · Estructura B201 / p. 5","status":"documentado"},{"label":"Cota superior absoluta","value":284.95,"unit":"m","source":"EST-OF-20260710 · Estructura B201 / p. 5","status":"documentado"},{"label":"Longitud","value":2,"unit":"m","source":"EST-OF-20260710 · Estructura B201 / p. 5","status":"documentado"},{"label":"Anchura","value":2,"unit":"m","source":"EST-OF-20260710 · Estructura B201 / p. 5","status":"documentado"},{"label":"Canto","value":0.7,"unit":"m","source":"EST-OF-20260710 · Estructura B201 / p. 5","status":"documentado"}],"geometry":[{"label":"Dimensiones de la caja local del elemento (X, Y, Z)","value":"2 × 2 × 0.7","unit":"m","source":"Malla triangulada del elemento en ejes locales del edificio","status":"derivado"},{"label":"Cota mínima absoluta de la malla","value":284.25,"unit":"m","source":"Malla de proyecto y origen altimétrico 285 m","status":"derivado"},{"label":"Cota máxima absoluta de la malla","value":284.95,"unit":"m","source":"Malla de proyecto y origen altimétrico 285 m","status":"derivado"},{"label":"Volumen geométrico bruto","value":2.8,"unit":"m³","source":"Malla cerrada del elemento","status":"derivado"}],"notes":["Las dimensiones documentadas proceden de anotaciones o cuadros; la caja y el volumen se calculan a partir de la malla.","El volumen es exclusivamente geométrico y bruto; no representa una medición neta de material ni una cantidad de compra."]} | {"documentId":"EST-OF-20260710","title":"Planos de estructura del edificio de oficinas","date":"2026-07-10","sheet":"Estructura B201 / p. 5"} | derivado | ["El plano general de 2026-07-31 mantiene el edificio de oficinas de 200 m², mientras documentación anterior indica su supresión. Se conserva lo dibujado, pendiente de confirmación de la propiedad y del equipo de diseño.","Profundidad de sustitución o de hormigón ciclópeo bajo zapatas dependiente del terreno real; no modelada sin datos.","Registro de líneas del PDF general, envolvente de 20 × 10 m; eje local 1 al norte y acceso del lado A al oeste. Estimación de trabajo de implantación de ±0,15 m, pendiente de CAD; no constituye una precisión topográfica garantizada."] | {"horizontalStatus":"derivado","verticalStatus":"derivado","baseElevationM":285.95,"note":"Registro de líneas del PDF general, envolvente de 20 × 10 m; eje local 1 al norte y acceso del lado A al oeste. Estimación de trabajo de implantación de ±0,15 m, pendiente de CAD; no constituye una precisión topográfica garantizada."} | {"boundingBoxM":{"min":[23.254833,71.015826,-0.75],"max":[25.508602,73.269596,-0.05]},"extentsM":[2.253769,2.25377,0.7],"meshSurfaceM2":13.600001,"meshVolumeM3":2.8,"closedSolid":true,"basis":"Geometría triangulada releída del IFC; envolventes y magnitudes no contractuales."} | {"profileId":"concrete_ha30","name":"Hormigón HA-30","materialName":"Hormigón armado HA-30","physicalMaterialStatus":"known","physicalMaterialSource":"EST-OF-20260710 · Estructura B201 / p. 5; nota de resistencia de zapatas y vigas de atado","appearanceStatus":"criterio_visual","appearanceBasis":"Interpretación visual del material documental; el acabado, tono y parámetros PBR no son una especificación contractual.","note":"La apariencia gráfica no modifica ni confirma la especificación física del material."} | {"elementId":"office_0259","ifcGuid":"1_lyALvADPAO1w7Dw2BM5g","ifcClass":"IfcFooting","buildingId":"office","buildingName":"Edificio de oficinas","sourceDocumentId":"EST-OF-20260710","sourceRepresentationKind":"documentary_mesh"} | {"layerId":"foundations","layerName":"Cimentaciones","role":"Zapata aislada","basis":"Clasificación por función del elemento; no modifica las especificaciones documentales."} | {"profileId":"concrete_ha30","name":"Hormigón HA-30","status":"criterio_visual","basis":"Interpretación visual del material documental; el acabado, tono y parámetros PBR no son una especificación contractual.","physicalMaterialUnchanged":true} | 2.8 | Hormigón armado HA-30 | Hormigón HA-30 | office_0259 | EST-OF-20260710 · Estructura B201 / p. 5; nota de resistencia de zapatas y vigas de atado | known | concrete_ha30 | [0.658824,0.658824,0.623529] | 0.94 | Cimentación; BIM · Cimentaciones | Material: Hormigón armado HA-30; JH_DimensionesDelModelo - Dimensiones de la caja local del elemento (X, Y, Z): 2 × 2 × 0.7; Cota mínima absoluta de la malla: 284.25 m; Cota máxima absoluta de la malla: 284.95 m; Volumen geométrico bruto: 2.8 m3; Pset_FootingCommon - Reference: office_0259; Qto_FootingBaseQuantities - GrossVolume: 2.8 m3; JH_InformacionBIM - level: Planta baja; ifcAssociations: {"material":true,"document":true,"quantities":true,"containerGuid":"3ztlotcerHPueDgxP84R6z","containerName":"Planta baja"}; JH_Trazabilidad - Planos de referencia: EST-OF-20260710 · Estructura B201 / p. 5; Edificio: Edificio de oficinas; Base geométrica: Dimensiones y cotas documentadas en el cuadro de cimentación.; Sistema de coordenadas: Coordenadas de proyecto en metros; sumar (729400, 4301550, 285) para recuperar las coordenadas UTM y cotas de los planos.; Uso del modelo: Reconstrucción tridimensional de la documentación y revisión preliminar de coordinación; pendiente de revisión por el equipo de diseño.; Hormigón: HA-30; Longitud (m): 2; Anchura (m): 2; Canto (m): 0.7; Cota inferior absoluta (m): 284.25; Cota superior absoluta (m): 284.95; Tratamiento del terreno de apoyo: Profundidad de sustitución o de hormigón ciclópeo bajo zapatas dependiente del terreno real; no modelada sin datos.; Verificación de la malla: Malla cerrada, orientación coherente de las caras y volumen positivo.; Referencia de implantación: Plano general U004 de 2026-07-31; geometría vectorial del PDF registrada con las coordenadas de lindero indicadas.; Estado de la implantación: Registro de líneas del PDF general, envolvente de 20 × 10 m; eje local 1 al norte y acceso del lado A al oeste. Estimación de trabajo de implantación de ±0,15 m, pendiente de CAD; no constituye una precisión topográfica garantizada.; Identificador del elemento: office_0259; Disciplina: Cimentación; Clase IFC: IfcFooting; Fase del modelo: V0.1 · Reconstrucción documental y coordinación preliminar; Representación geométrica: Sólido de malla triangular cerrada en IFC4; Aplicabilidad de las mediciones: Volumen exclusivamente geométrico; los espesores de representación, las simplificaciones y las envolventes no constituyen mediciones de compra, ejecución, fabricación ni volumen neto de material.; Referencia del material: EST-OF-20260710 · Estructura B201 / p. 5; nota de resistencia de zapatas y vigas de atado; Cota de planta baja terminada (m): 285.95; Discrepancia entre versiones: El plano general de 2026-07-31 mantiene el edificio de oficinas de 200 m², mientras documentación anterior indica su supresión. Se conserva lo dibujado, pendiente de confirmación de la propiedad y del equipo de diseño.; JH_DimensionesDocumentadas - Cota inferior absoluta: 284.25 m; Cota superior absoluta: 284.95 m; Longitud: 2 m; Anchura: 2 m; Canto: 0.7 m
Cimentación común MAC · losa inferior | Parcela industrial Jinhong | Cimentación industrial | Cimentaciones de equipos y pedestales del fabricante · revisión recibida 04/09/2026 | 18.9726 | 11.4532 | 0.8 | 368.98 | 130.312 | process_plant | Zona de separación de aire | {"name":"Hormigón armado · clase pendiente de confirmar","status":"Clase no confirmada en la hoja de equipo","source":"Geometría de cimentación del fabricante; no se extrapola HA-30 de la nota de pedestales."} | {"documented":[{"label":"Extensión local X","value":17.9,"unit":"m","source":"23B3/23B8, 23B3/23CC, 23B3/23CD, 23B3/23D0, 288F5","status":"derivada del contorno CAD"},{"label":"Extensión local Y","value":9.1,"unit":"m","source":"23B3/23B8, 23B3/23CC, 23B3/23CD, 23B3/23D0, 288F5","status":"derivada del contorno CAD"},{"label":"Cota inferior relativa adoptada","value":-1,"unit":"m","source":"1–1","status":"documentada"},{"label":"Cota superior relativa adoptada","value":-0.2,"unit":"m","source":"1–1","status":"documentada / separación por material"}],"geometry":[{"label":"Extensión de la malla en X","value":18.972642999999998,"unit":"m","source":"Geometría releída del IFC; datum absoluto de proceso provisional","status":"derivado"},{"label":"Extensión de la malla en Y","value":11.453246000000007,"unit":"m","source":"Geometría releída del IFC; datum absoluto de proceso provisional","status":"derivado"},{"label":"Extensión de la malla en Z","value":0.8,"unit":"m","source":"Geometría releída del IFC; datum absoluto de proceso provisional","status":"derivado"},{"label":"Cota inferior de visualización","value":285.1,"unit":"m","source":"Geometría releída del IFC; datum absoluto de proceso provisional","status":"derivado"},{"label":"Cota superior de visualización","value":285.9,"unit":"m","source":"Geometría releída del IFC; datum absoluto de proceso provisional","status":"derivado"}]} | {"documentId":"LHD2609-JG00100-20260904","title":"Cimentaciones de equipos y pedestales del fabricante · revisión recibida 04/09/2026","date":"2026-09-04","sheet":"1–1","fileName":"LHD2609-JG00100_20260904.dwg","revisionCaveat":"Fecha de revisión tomada del nombre recibido; cajetines internos mantienen 02/07/2026 y algunos textos de plantilla.","sourceFileSha256":"b42eb027b7bc0b14c38d1d13514f4899b58a732aa8d0ba2ccf10fa2fc3192890"} | provisional | [] | {"Cota inferior relativa (m)":-1,"Cota superior relativa (m)":-0.2,"Cero absoluto de visualización (m)":286.1,"Estado del cero absoluto":"Provisional","Criterio":"Las cotas relativas proceden del dibujo; la equivalencia absoluta no está confirmada."} | {"boundingBoxM":{"min":[46.564344,66.729997,0.1],"max":[65.536987,78.183243,0.9]},"extentsM":[18.972643,11.453246,0.8],"meshSurfaceM2":368.980009,"meshVolumeM3":130.312003,"closedSolid":true,"basis":"Magnitudes de las mallas representadas, no cantidades certificadas de obra, compra o fabricación. Las partes pueden compartir superficies; no se suman como un despiece de materiales."} | {"profileId":"concrete_reinforced","name":"Hormigón armado · gris natural","materialName":"Hormigón armado · clase pendiente de confirmar","physicalMaterialStatus":"Clase no confirmada en la hoja de equipo","physicalMaterialSource":"Geometría de cimentación del fabricante; no se extrapola HA-30 de la nota de pedestales.","appearanceStatus":"criterio_visual","appearanceBasis":"Interpretación visual del material documental; el acabado, tono y parámetros PBR no son una especificación contractual.","note":"La apariencia gráfica no modifica ni confirma la especificación física del material."} | {"elementId":"found_0904_ee421d36db9553","ifcGuid":"2c_30fZRLJrectwWrPJwlR","ifcClass":"IfcFooting","buildingId":"process_plant","buildingName":"Zona de separación de aire","sourceDocumentId":"LHD2609-JG00100-20260904","sourceRepresentationKind":"foundation"} | {"layerId":"foundations","layerName":"Cimentaciones","role":"Cimentación industrial","basis":"Clasificación por función del elemento; no modifica las especificaciones documentales."} | {"profileId":"concrete_reinforced","name":"Hormigón armado · gris natural","status":"criterio_visual","basis":"Interpretación visual del material documental; el acabado, tono y parámetros PBR no son una especificación contractual.","physicalMaterialUnchanged":true} | 130.312 | Hormigón armado · clase pendiente de confirmar | Hormigón armado · gris natural | found_0904_ee421d36db9553 | Geometría de cimentación del fabricante; no se extrapola HA-30 de la nota de pedestales. | Clase no confirmada en la hoja de equipo | concrete_reinforced | [0.666667,0.662745,0.619608] | 0.96 | Zona de separación de aire; BIM · Cimentaciones | 18.9726 | 11.4532 | 0.8 | 285.1 | 285.9 | F-MAC | ["AC1001A","AC1001B","AC1001C"] | [] | 1–1 | ["23B3/23B8","23B3/23CC","23B3/23CD","23B3/23D0","288F5","23B3/23C7","23B3/F6F1","288F5","23B3/23C5","23B3/F6F1","288F5","23B3/23C4","23B3/F6F1","288F5"] | F-MAC/Cimentación común MAC · losa inferior | foundation | Geometría de fabricante; implantación absoluta provisional | AC1001A, AC1001B, AC1001C | Cimentaciones de equipos y pedestales del fabricante · revisión recibida 04/09/2026 | 23B3/23B8, 23B3/23CC, 23B3/23CD, 23B3/23D0, 288F5 | -1 | -0.2 | 162.89 | Cotas relativas del dibujo. La equivalencia con un datum absoluto está pendiente. | Z del modelo = cota relativa + 1,10 m. Correspondencia provisional con 286,10 m; no es cota de obra confirmada. | Contornos y sección documentados por el fabricante | 17.9 | 9.1
Cimentación común MAC · losa superior con dos canales de 400 mm | Parcela industrial Jinhong | Cimentación industrial | Cimentaciones de equipos y pedestales del fabricante · revisión recibida 04/09/2026 | 18.9726 | 11.4532 | 0.4 | 347.38 | 63.636 | process_plant | Zona de separación de aire | {"name":"Hormigón armado · clase pendiente de confirmar","status":"Clase no confirmada en la hoja de equipo","source":"Geometría de cimentación del fabricante; no se extrapola HA-30 de la nota de pedestales."} | {"documented":[{"label":"Extensión local X","value":17.9,"unit":"m","source":"23B3/23B8, 23B3/23CC, 23B3/23CD, 23B3/23D0, 288F5","status":"derivada del contorno CAD"},{"label":"Extensión local Y","value":9.1,"unit":"m","source":"23B3/23B8, 23B3/23CC, 23B3/23CD, 23B3/23D0, 288F5","status":"derivada del contorno CAD"},{"label":"Cota inferior relativa adoptada","value":-0.2,"unit":"m","source":"1–1","status":"documentada"},{"label":"Cota superior relativa adoptada","value":0.2,"unit":"m","source":"1–1","status":"documentada / separación por material"}],"geometry":[{"label":"Extensión de la malla en X","value":18.972642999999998,"unit":"m","source":"Geometría releída del IFC; datum absoluto de proceso provisional","status":"derivado"},{"label":"Extensión de la malla en Y","value":11.453246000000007,"unit":"m","source":"Geometría releída del IFC; datum absoluto de proceso provisional","status":"derivado"},{"label":"Extensión de la malla en Z","value":0.4,"unit":"m","source":"Geometría releída del IFC; datum absoluto de proceso provisional","status":"derivado"},{"label":"Cota inferior de visualización","value":285.9,"unit":"m","source":"Geometría releída del IFC; datum absoluto de proceso provisional","status":"derivado"},{"label":"Cota superior de visualización","value":286.3,"unit":"m","source":"Geometría releída del IFC; datum absoluto de proceso provisional","status":"derivado"}]} | {"documentId":"LHD2609-JG00100-20260904","title":"Cimentaciones de equipos y pedestales del fabricante · revisión recibida 04/09/2026","date":"2026-09-04","sheet":"1–1","fileName":"LHD2609-JG00100_20260904.dwg","revisionCaveat":"Fecha de revisión tomada del nombre recibido; cajetines internos mantienen 02/07/2026 y algunos textos de plantilla.","sourceFileSha256":"b42eb027b7bc0b14c38d1d13514f4899b58a732aa8d0ba2ccf10fa2fc3192890"} | provisional | [] | {"Cota inferior relativa (m)":-0.2,"Cota superior relativa (m)":0.2,"Cero absoluto de visualización (m)":286.1,"Estado del cero absoluto":"Provisional","Criterio":"Las cotas relativas proceden del dibujo; la equivalencia absoluta no está confirmada."} | {"boundingBoxM":{"min":[46.564344,66.729997,0.9],"max":[65.536987,78.183243,1.3]},"extentsM":[18.972643,11.453246,0.4],"meshSurfaceM2":347.380002,"meshVolumeM3":63.636,"closedSolid":true,"basis":"Magnitudes de las mallas representadas, no cantidades certificadas de obra, compra o fabricación. Las partes pueden compartir superficies; no se suman como un despiece de materiales."} | {"profileId":"concrete_reinforced","name":"Hormigón armado · gris natural","materialName":"Hormigón armado · clase pendiente de confirmar","physicalMaterialStatus":"Clase no confirmada en la hoja de equipo","physicalMaterialSource":"Geometría de cimentación del fabricante; no se extrapola HA-30 de la nota de pedestales.","appearanceStatus":"criterio_visual","appearanceBasis":"Interpretación visual del material documental; el acabado, tono y parámetros PBR no son una especificación contractual.","note":"La apariencia gráfica no modifica ni confirma la especificación física del material."} | {"elementId":"found_0904_23cc68a21c3fa1","ifcGuid":"2ueye5NmLT3hsof3Qpotmz","ifcClass":"IfcFooting","buildingId":"process_plant","buildingName":"Zona de separación de aire","sourceDocumentId":"LHD2609-JG00100-20260904","sourceRepresentationKind":"foundation"} | {"layerId":"foundations","layerName":"Cimentaciones","role":"Cimentación industrial","basis":"Clasificación por función del elemento; no modifica las especificaciones documentales."} | {"profileId":"concrete_reinforced","name":"Hormigón armado · gris natural","status":"criterio_visual","basis":"Interpretación visual del material documental; el acabado, tono y parámetros PBR no son una especificación contractual.","physicalMaterialUnchanged":true} | 63.636 | Hormigón armado · clase pendiente de confirmar | Hormigón armado · gris natural | found_0904_23cc68a21c3fa1 | Geometría de cimentación del fabricante; no se extrapola HA-30 de la nota de pedestales. | Clase no confirmada en la hoja de equipo | concrete_reinforced | [0.666667,0.662745,0.619608] | 0.96 | Zona de separación de aire; BIM · Cimentaciones | 18.9726 | 11.4532 | 0.4 | 285.9 | 286.3 | F-MAC | ["AC1001A","AC1001B","AC1001C"] | [] | 1–1 | ["23B3/23B8","23B3/23CC","23B3/23CD","23B3/23D0","288F5","23B3/23C7","23B3/F6F1","288F5","23B3/23C5","23B3/F6F1","288F5","23B3/23C4","23B3/F6F1","288F5"] | F-MAC/Cimentación común MAC · losa superior con dos canales de 400 mm | foundation | Geometría de fabricante; implantación absoluta provisional | AC1001A, AC1001B, AC1001C | Cimentaciones de equipos y pedestales del fabricante · revisión recibida 04/09/2026 | 23B3/23B8, 23B3/23CC, 23B3/23CD, 23B3/23D0, 288F5 | -0.2 | 0.2 | 159.09 | Cotas relativas del dibujo. La equivalencia con un datum absoluto está pendiente. | Z del modelo = cota relativa + 1,10 m. Correspondencia provisional con 286,10 m; no es cota de obra confirmada. | Contornos y sección documentados por el fabricante | 17.9 | 9.1
Plinto del compresor AC1001A · resalto de hormigón | Parcela industrial Jinhong | Cimentación industrial | Cimentaciones de equipos y pedestales del fabricante · revisión recibida 04/09/2026 | 3.43758 | 5.91556 | 0.15 | 32.73 | 2.268 | process_plant | Zona de separación de aire | {"name":"Hormigón armado · clase pendiente de confirmar","status":"Clase no confirmada en la hoja de equipo","source":"Geometría de cimentación del fabricante; no se extrapola HA-30 de la nota de pedestales."} | {"documented":[{"label":"Extensión local X","value":2.7,"unit":"m","source":"23B3/23C7, 23B3/F6F1, 288F5","status":"derivada del contorno CAD"},{"label":"Extensión local Y","value":5.6,"unit":"m","source":"23B3/23C7, 23B3/F6F1, 288F5","status":"derivada del contorno CAD"},{"label":"Cota inferior relativa adoptada","value":0.2,"unit":"m","source":"1–1","status":"documentada"},{"label":"Cota superior relativa adoptada","value":0.35,"unit":"m","source":"1–1","status":"documentada / separación por material"}],"geometry":[{"label":"Extensión de la malla en X","value":3.437579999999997,"unit":"m","source":"Geometría releída del IFC; datum absoluto de proceso provisional","status":"derivado"},{"label":"Extensión de la malla en Y","value":5.915563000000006,"unit":"m","source":"Geometría releída del IFC; datum absoluto de proceso provisional","status":"derivado"},{"label":"Extensión de la malla en Z","value":0.1499999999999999,"unit":"m","source":"Geometría releída del IFC; datum absoluto de proceso provisional","status":"derivado"},{"label":"Cota inferior de visualización","value":286.3,"unit":"m","source":"Geometría releída del IFC; datum absoluto de proceso provisional","status":"derivado"},{"label":"Cota superior de visualización","value":286.45,"unit":"m","source":"Geometría releída del IFC; datum absoluto de proceso provisional","status":"derivado"}]} | {"documentId":"LHD2609-JG00100-20260904","title":"Cimentaciones de equipos y pedestales del fabricante · revisión recibida 04/09/2026","date":"2026-09-04","sheet":"1–1","fileName":"LHD2609-JG00100_20260904.dwg","revisionCaveat":"Fecha de revisión tomada del nombre recibido; cajetines internos mantienen 02/07/2026 y algunos textos de plantilla.","sourceFileSha256":"b42eb027b7bc0b14c38d1d13514f4899b58a732aa8d0ba2ccf10fa2fc3192890"} | provisional | [] | {"Cota inferior relativa (m)":0.2,"Cota superior relativa (m)":0.35,"Cero absoluto de visualización (m)":286.1,"Estado del cero absoluto":"Provisional","Criterio":"Las cotas relativas proceden del dibujo; la equivalencia absoluta no está confirmada."} | {"boundingBoxM":{"min":[48.05281,70.81635,1.3],"max":[51.49039,76.731913,1.45]},"extentsM":[3.43758,5.915563,0.15],"meshSurfaceM2":32.729997,"meshVolumeM3":2.268,"closedSolid":true,"basis":"Magnitudes de las mallas representadas, no cantidades certificadas de obra, compra o fabricación. Las partes pueden compartir superficies; no se suman como un despiece de materiales."} | {"profileId":"concrete_reinforced","name":"Hormigón armado · gris natural","materialName":"Hormigón armado · clase pendiente de confirmar","physicalMaterialStatus":"Clase no confirmada en la hoja de equipo","physicalMaterialSource":"Geometría de cimentación del fabricante; no se extrapola HA-30 de la nota de pedestales.","appearanceStatus":"criterio_visual","appearanceBasis":"Interpretación visual del material documental; el acabado, tono y parámetros PBR no son una especificación contractual.","note":"La apariencia gráfica no modifica ni confirma la especificación física del material."} | {"elementId":"found_0904_bb30905ff8ceb7","ifcGuid":"2x$qaCloHPQeekDlueZaHS","ifcClass":"IfcFooting","buildingId":"process_plant","buildingName":"Zona de separación de aire","sourceDocumentId":"LHD2609-JG00100-20260904","sourceRepresentationKind":"foundation"} | {"layerId":"foundations","layerName":"Cimentaciones","role":"Cimentación industrial","basis":"Clasificación por función del elemento; no modifica las especificaciones documentales."} | {"profileId":"concrete_reinforced","name":"Hormigón armado · gris natural","status":"criterio_visual","basis":"Interpretación visual del material documental; el acabado, tono y parámetros PBR no son una especificación contractual.","physicalMaterialUnchanged":true} | 2.268 | Hormigón armado · clase pendiente de confirmar | Hormigón armado · gris natural | found_0904_bb30905ff8ceb7 | Geometría de cimentación del fabricante; no se extrapola HA-30 de la nota de pedestales. | Clase no confirmada en la hoja de equipo | concrete_reinforced | [0.666667,0.662745,0.619608] | 0.96 | Zona de separación de aire; BIM · Cimentaciones | 3.43758 | 5.91556 | 0.15 | 286.3 | 286.45 | F-MAC | ["AC1001A"] | [] | 1–1 | ["23B3/23C7","23B3/F6F1","288F5"] | F-MAC/Plinto del compresor AC1001A · resalto de hormigón | foundation | Geometría de fabricante; implantación absoluta provisional | AC1001A | Cimentaciones de equipos y pedestales del fabricante · revisión recibida 04/09/2026 | 23B3/23C7, 23B3/F6F1, 288F5 | 0.2 | 0.35 | 15.12 | Cotas relativas del dibujo. La equivalencia con un datum absoluto está pendiente. | Z del modelo = cota relativa + 1,10 m. Correspondencia provisional con 286,10 m; no es cota de obra confirmada. | Contornos y sección documentados por el fabricante | 2.7 | 5.6
Plinto del compresor AC1001B · resalto de hormigón | Parcela industrial Jinhong | Cimentación industrial | Cimentaciones de equipos y pedestales del fabricante · revisión recibida 04/09/2026 | 3.43758 | 5.91556 | 0.15 | 32.73 | 2.268 | process_plant | Zona de separación de aire | {"name":"Hormigón armado · clase pendiente de confirmar","status":"Clase no confirmada en la hoja de equipo","source":"Geometría de cimentación del fabricante; no se extrapola HA-30 de la nota de pedestales."} | {"documented":[{"label":"Extensión local X","value":2.7,"unit":"m","source":"23B3/23C5, 23B3/F6F1, 288F5","status":"derivada del contorno CAD"},{"label":"Extensión local Y","value":5.6,"unit":"m","source":"23B3/23C5, 23B3/F6F1, 288F5","status":"derivada del contorno CAD"},{"label":"Cota inferior relativa adoptada","value":0.2,"unit":"m","source":"1–1","status":"documentada"},{"label":"Cota superior relativa adoptada","value":0.35,"unit":"m","source":"1–1","status":"documentada / separación por material"}],"geometry":[{"label":"Extensión de la malla en X","value":3.437580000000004,"unit":"m","source":"Geometría releída del IFC; datum absoluto de proceso provisional","status":"derivado"},{"label":"Extensión de la malla en Y","value":5.915563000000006,"unit":"m","source":"Geometría releída del IFC; datum absoluto de proceso provisional","status":"derivado"},{"label":"Extensión de la malla en Z","value":0.1499999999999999,"unit":"m","source":"Geometría releída del IFC; datum absoluto de proceso provisional","status":"derivado"},{"label":"Cota inferior de visualización","value":286.3,"unit":"m","source":"Geometría releída del IFC; datum absoluto de proceso provisional","status":"derivado"},{"label":"Cota superior de visualización","value":286.45,"unit":"m","source":"Geometría releída del IFC; datum absoluto de proceso provisional","status":"derivado"}]} | {"documentId":"LHD2609-JG00100-20260904","title":"Cimentaciones de equipos y pedestales del fabricante · revisión recibida 04/09/2026","date":"2026-09-04","sheet":"1–1","fileName":"LHD2609-JG00100_20260904.dwg","revisionCaveat":"Fecha de revisión tomada del nombre recibido; cajetines internos mantienen 02/07/2026 y algunos textos de plantilla.","sourceFileSha256":"b42eb027b7bc0b14c38d1d13514f4899b58a732aa8d0ba2ccf10fa2fc3192890"} | provisional | [] | {"Cota inferior relativa (m)":0.2,"Cota superior relativa (m)":0.35,"Cero absoluto de visualización (m)":286.1,"Estado del cero absoluto":"Provisional","Criterio":"Las cotas relativas proceden del dibujo; la equivalencia absoluta no está confirmada."} | {"boundingBoxM":{"min":[54.393167,69.944645,1.3],"max":[57.830747,75.860208,1.45]},"extentsM":[3.43758,5.915563,0.15],"meshSurfaceM2":32.729997,"meshVolumeM3":2.268,"closedSolid":true,"basis":"Magnitudes de las mallas representadas, no cantidades certificadas de obra, compra o fabricación. Las partes pueden compartir superficies; no se suman como un despiece de materiales."} | {"profileId":"concrete_reinforced","name":"Hormigón armado · gris natural","materialName":"Hormigón armado · clase pendiente de confirmar","physicalMaterialStatus":"Clase no confirmada en la hoja de equipo","physicalMaterialSource":"Geometría de cimentación del fabricante; no se extrapola HA-30 de la nota de pedestales.","appearanceStatus":"criterio_visual","appearanceBasis":"Interpretación visual del material documental; el acabado, tono y parámetros PBR no son una especificación contractual.","note":"La apariencia gráfica no modifica ni confirma la especificación física del material."} | {"elementId":"found_0904_4ec3b942771d61","ifcGuid":"0awa6fpxHIiQQ4m0G2ZwHC","ifcClass":"IfcFooting","buildingId":"process_plant","buildingName":"Zona de separación de aire","sourceDocumentId":"LHD2609-JG00100-20260904","sourceRepresentationKind":"foundation"} | {"layerId":"foundations","layerName":"Cimentaciones","role":"Cimentación industrial","basis":"Clasificación por función del elemento; no modifica las especificaciones documentales."} | {"profileId":"concrete_reinforced","name":"Hormigón armado · gris natural","status":"criterio_visual","basis":"Interpretación visual del material documental; el acabado, tono y parámetros PBR no son una especificación contractual.","physicalMaterialUnchanged":true} | 2.268 | Hormigón armado · clase pendiente de confirmar | Hormigón armado · gris natural | found_0904_4ec3b942771d61 | Geometría de cimentación del fabricante; no se extrapola HA-30 de la nota de pedestales. | Clase no confirmada en la hoja de equipo | concrete_reinforced | [0.666667,0.662745,0.619608] | 0.96 | Zona de separación de aire; BIM · Cimentaciones | 3.43758 | 5.91556 | 0.15 | 286.3 | 286.45 | F-MAC | ["AC1001B"] | [] | 1–1 | ["23B3/23C5","23B3/F6F1","288F5"] | F-MAC/Plinto del compresor AC1001B · resalto de hormigón | foundation | Geometría de fabricante; implantación absoluta provisional | AC1001B | Cimentaciones de equipos y pedestales del fabricante · revisión recibida 04/09/2026 | 23B3/23C5, 23B3/F6F1, 288F5 | 0.2 | 0.35 | 15.12 | Cotas relativas del dibujo. La equivalencia con un datum absoluto está pendiente. | Z del modelo = cota relativa + 1,10 m. Correspondencia provisional con 286,10 m; no es cota de obra confirmada. | Contornos y sección documentados por el fabricante | 2.7 | 5.6
Plinto del compresor AC1001C · resalto de hormigón | Parcela industrial Jinhong | Cimentación industrial | Cimentaciones de equipos y pedestales del fabricante · revisión recibida 04/09/2026 | 3.43758 | 5.91556 | 0.15 | 32.73 | 2.268 | process_plant | Zona de separación de aire | {"name":"Hormigón armado · clase pendiente de confirmar","status":"Clase no confirmada en la hoja de equipo","source":"Geometría de cimentación del fabricante; no se extrapola HA-30 de la nota de pedestales."} | {"documented":[{"label":"Extensión local X","value":2.7,"unit":"m","source":"23B3/23C4, 23B3/F6F1, 288F5","status":"derivada del contorno CAD"},{"label":"Extensión local Y","value":5.6,"unit":"m","source":"23B3/23C4, 23B3/F6F1, 288F5","status":"derivada del contorno CAD"},{"label":"Cota inferior relativa adoptada","value":0.2,"unit":"m","source":"1–1","status":"documentada"},{"label":"Cota superior relativa adoptada","value":0.35,"unit":"m","source":"1–1","status":"documentada / separación por material"}],"geometry":[{"label":"Extensión de la malla en X","value":3.4375809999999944,"unit":"m","source":"Geometría releída del IFC; datum absoluto de proceso provisional","status":"derivado"},{"label":"Extensión de la malla en Y","value":5.915563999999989,"unit":"m","source":"Geometría releída del IFC; datum absoluto de proceso provisional","status":"derivado"},{"label":"Extensión de la malla en Z","value":0.1499999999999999,"unit":"m","source":"Geometría releída del IFC; datum absoluto de proceso provisional","status":"derivado"},{"label":"Cota inferior de visualización","value":286.3,"unit":"m","source":"Geometría releída del IFC; datum absoluto de proceso provisional","status":"derivado"},{"label":"Cota superior de visualización","value":286.45,"unit":"m","source":"Geometría releída del IFC; datum absoluto de proceso provisional","status":"derivado"}]} | {"documentId":"LHD2609-JG00100-20260904","title":"Cimentaciones de equipos y pedestales del fabricante · revisión recibida 04/09/2026","date":"2026-09-04","sheet":"1–1","fileName":"LHD2609-JG00100_20260904.dwg","revisionCaveat":"Fecha de revisión tomada del nombre recibido; cajetines internos mantienen 02/07/2026 y algunos textos de plantilla.","sourceFileSha256":"b42eb027b7bc0b14c38d1d13514f4899b58a732aa8d0ba2ccf10fa2fc3192890"} | provisional | [] | {"Cota inferior relativa (m)":0.2,"Cota superior relativa (m)":0.35,"Cero absoluto de visualización (m)":286.1,"Estado del cero absoluto":"Provisional","Criterio":"Las cotas relativas proceden del dibujo; la equivalencia absoluta no está confirmada."} | {"boundingBoxM":{"min":[60.733524,69.072939,1.3],"max":[64.171105,74.988503,1.45]},"extentsM":[3.437581,5.915564,0.15],"meshSurfaceM2":32.730012,"meshVolumeM3":2.268001,"closedSolid":true,"basis":"Magnitudes de las mallas representadas, no cantidades certificadas de obra, compra o fabricación. Las partes pueden compartir superficies; no se suman como un despiece de materiales."} | {"profileId":"concrete_reinforced","name":"Hormigón armado · gris natural","materialName":"Hormigón armado · clase pendiente de confirmar","physicalMaterialStatus":"Clase no confirmada en la hoja de equipo","physicalMaterialSource":"Geometría de cimentación del fabricante; no se extrapola HA-30 de la nota de pedestales.","appearanceStatus":"criterio_visual","appearanceBasis":"Interpretación visual del material documental; el acabado, tono y parámetros PBR no son una especificación contractual.","note":"La apariencia gráfica no modifica ni confirma la especificación física del material."} | {"elementId":"found_0904_3e524c68a2f394","ifcGuid":"2NwcGQwmTIfv0BAJ349Rii","ifcClass":"IfcFooting","buildingId":"process_plant","buildingName":"Zona de separación de aire","sourceDocumentId":"LHD2609-JG00100-20260904","sourceRepresentationKind":"foundation"} | {"layerId":"foundations","layerName":"Cimentaciones","role":"Cimentación industrial","basis":"Clasificación por función del elemento; no modifica las especificaciones documentales."} | {"profileId":"concrete_reinforced","name":"Hormigón armado · gris natural","status":"criterio_visual","basis":"Interpretación visual del material documental; el acabado, tono y parámetros PBR no son una especificación contractual.","physicalMaterialUnchanged":true} | 2.268 | Hormigón armado · clase pendiente de confirmar | Hormigón armado · gris natural | found_0904_3e524c68a2f394 | Geometría de cimentación del fabricante; no se extrapola HA-30 de la nota de pedestales. | Clase no confirmada en la hoja de equipo | concrete_reinforced | [0.666667,0.662745,0.619608] | 0.96 | Zona de separación de aire; BIM · Cimentaciones | 3.43758 | 5.91556 | 0.15 | 286.3 | 286.45 | F-MAC | ["AC1001C"] | [] | 1–1 | ["23B3/23C4","23B3/F6F1","288F5"] | F-MAC/Plinto del compresor AC1001C · resalto de hormigón | foundation | Geometría de fabricante; implantación absoluta provisional | AC1001C | Cimentaciones de equipos y pedestales del fabricante · revisión recibida 04/09/2026 | 23B3/23C4, 23B3/F6F1, 288F5 | 0.2 | 0.35 | 15.12 | Cotas relativas del dibujo. La equivalencia con un datum absoluto está pendiente. | Z del modelo = cota relativa + 1,10 m. Correspondencia provisional con 286,10 m; no es cota de obra confirmada. | Contornos y sección documentados por el fabricante | 2.7 | 5.6
Base del preenfriador RU1101A · cuerpo de hormigón | Parcela industrial Jinhong | Cimentación industrial | Cimentaciones de equipos y pedestales del fabricante · revisión recibida 04/09/2026 | 4.26237 | 2.72431 | 1.15 | 31.86 | 10.12 | process_plant | Zona de separación de aire | {"name":"Hormigón armado · clase pendiente de confirmar","status":"Clase no confirmada en la hoja de equipo","source":"Geometría de cimentación del fabricante; no se extrapola HA-30 de la nota de pedestales."} | {"documented":[{"label":"Extensión local X","value":4.0,"unit":"m","source":"2934/2402, 28CEA","status":"derivada del contorno CAD"},{"label":"Extensión local Y","value":2.2,"unit":"m","source":"2934/2402, 28CEA","status":"derivada del contorno CAD"},{"label":"Cota inferior relativa adoptada","value":-1,"unit":"m","source":"2–2","status":"interpretación con conflicto conservado"},{"label":"Cota superior relativa adoptada","value":0.15000000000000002,"unit":"m","source":"2–2","status":"documentada / separación por material"}],"geometry":[{"label":"Extensión de la malla en X","value":4.262372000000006,"unit":"m","source":"Geometría releída del IFC; datum absoluto de proceso provisional","status":"derivado"},{"label":"Extensión de la malla en Y","value":2.7243139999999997,"unit":"m","source":"Geometría releída del IFC; datum absoluto de proceso provisional","status":"derivado"},{"label":"Extensión de la malla en Z","value":1.15,"unit":"m","source":"Geometría releída del IFC; datum absoluto de proceso provisional","status":"derivado"},{"label":"Cota inferior de visualización","value":285.1,"unit":"m","source":"Geometría releída del IFC; datum absoluto de proceso provisional","status":"derivado"},{"label":"Cota superior de visualización","value":286.25,"unit":"m","source":"Geometría releída del IFC; datum absoluto de proceso provisional","status":"derivado"}]} | {"documentId":"LHD2609-JG00100-20260904","title":"Cimentaciones de equipos y pedestales del fabricante · revisión recibida 04/09/2026","date":"2026-09-04","sheet":"2–2","fileName":"LHD2609-JG00100_20260904.dwg","revisionCaveat":"Fecha de revisión tomada del nombre recibido; cajetines internos mantienen 02/07/2026 y algunos textos de plantilla.","sourceFileSha256":"b42eb027b7bc0b14c38d1d13514f4899b58a732aa8d0ba2ccf10fa2fc3192890"} | provisional | ["La etiqueta inferior indica −3,000 m, pero la sección y su cadena 200 + 1000 = 1200 mm indican −1,000 m. Se adopta −1,000 m para la geometría; pendiente de aclaración del fabricante."] | {"Cota inferior relativa (m)":-1,"Cota superior relativa (m)":0.15000000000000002,"Cero absoluto de visualización (m)":286.1,"Estado del cero absoluto":"Provisional","Criterio":"Las cotas relativas proceden del dibujo; la equivalencia absoluta no está confirmada."} | {"boundingBoxM":{"min":[47.013935,63.817207,0.1],"max":[51.276307,66.541521,1.25]},"extentsM":[4.262372,2.724314,1.15],"meshSurfaceM2":31.860003,"meshVolumeM3":10.120001,"closedSolid":true,"basis":"Magnitudes de las mallas representadas, no cantidades certificadas de obra, compra o fabricación. Las partes pueden compartir superficies; no se suman como un despiece de materiales."} | {"profileId":"concrete_reinforced","name":"Hormigón armado · gris natural","materialName":"Hormigón armado · clase pendiente de confirmar","physicalMaterialStatus":"Clase no confirmada en la hoja de equipo","physicalMaterialSource":"Geometría de cimentación del fabricante; no se extrapola HA-30 de la nota de pedestales.","appearanceStatus":"criterio_visual","appearanceBasis":"Interpretación visual del material documental; el acabado, tono y parámetros PBR no son una especificación contractual.","note":"La apariencia gráfica no modifica ni confirma la especificación física del material."} | {"elementId":"found_0904_0f2bad74c83724","ifcGuid":"1C8etMDybVSAf6hYbtAw8s","ifcClass":"IfcFooting","buildingId":"process_plant","buildingName":"Zona de separación de aire","sourceDocumentId":"LHD2609-JG00100-20260904","sourceRepresentationKind":"foundation"} | {"layerId":"foundations","layerName":"Cimentaciones","role":"Cimentación industrial","basis":"Clasificación por función del elemento; no modifica las especificaciones documentales."} | {"profileId":"concrete_reinforced","name":"Hormigón armado · gris natural","status":"criterio_visual","basis":"Interpretación visual del material documental; el acabado, tono y parámetros PBR no son una especificación contractual.","physicalMaterialUnchanged":true} | 10.12 | Hormigón armado · clase pendiente de confirmar | Hormigón armado · gris natural | found_0904_0f2bad74c83724 | Geometría de cimentación del fabricante; no se extrapola HA-30 de la nota de pedestales. | Clase no confirmada en la hoja de equipo | concrete_reinforced | [0.666667,0.662745,0.619608] | 0.96 | Zona de separación de aire; BIM · Cimentaciones | 4.26237 | 2.72431 | 1.15 | 285.1 | 286.25 | F-RU1101A | ["RU1101A"] | [] | 2–2 | ["2934/2402","28CEA"] | F-RU1101A/Base del preenfriador RU1101A · cuerpo de hormigón | foundation | Geometría de fabricante; implantación absoluta provisional | RU1101A | Cimentaciones de equipos y pedestales del fabricante · revisión recibida 04/09/2026 | 2934/2402, 28CEA | -1 | 0.15 | 8.8 | Cotas relativas del dibujo. La equivalencia con un datum absoluto está pendiente. | Z del modelo = cota relativa + 1,10 m. Correspondencia provisional con 286,10 m; no es cota de obra confirmada. | Sección y contornos del fabricante; incidencias conservadas | 4 | 2.2 | La etiqueta inferior indica −3,000 m, pero la sección y su cadena 200 + 1000 = 1200 mm indican −1,000 m. Se adopta −1,000 m para la geometría; pendiente de aclaración del fabricante.
Base del preenfriador RU1101B · cuerpo de hormigón | Parcela industrial Jinhong | Cimentación industrial | Cimentaciones de equipos y pedestales del fabricante · revisión recibida 04/09/2026 | 4.26237 | 2.72431 | 1.15 | 31.86 | 10.12 | process_plant | Zona de separación de aire | {"name":"Hormigón armado · clase pendiente de confirmar","status":"Clase no confirmada en la hoja de equipo","source":"Geometría de cimentación del fabricante; no se extrapola HA-30 de la nota de pedestales."} | {"documented":[{"label":"Extensión local X","value":4.0,"unit":"m","source":"2933/2402, 28CEA","status":"derivada del contorno CAD"},{"label":"Extensión local Y","value":2.2,"unit":"m","source":"2933/2402, 28CEA","status":"derivada del contorno CAD"},{"label":"Cota inferior relativa adoptada","value":-1,"unit":"m","source":"2–2","status":"interpretación con conflicto conservado"},{"label":"Cota superior relativa adoptada","value":0.15000000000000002,"unit":"m","source":"2–2","status":"documentada / separación por material"}],"geometry":[{"label":"Extensión de la malla en X","value":4.262371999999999,"unit":"m","source":"Geometría releída del IFC; datum absoluto de proceso provisional","status":"derivado"},{"label":"Extensión de la malla en Y","value":2.7243139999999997,"unit":"m","source":"Geometría releída del IFC; datum absoluto de proceso provisional","status":"derivado"},{"label":"Extensión de la malla en Z","value":1.15,"unit":"m","source":"Geometría releída del IFC; datum absoluto de proceso provisional","status":"derivado"},{"label":"Cota inferior de visualización","value":285.1,"unit":"m","source":"Geometría releída del IFC; datum absoluto de proceso provisional","status":"derivado"},{"label":"Cota superior de visualización","value":286.25,"unit":"m","source":"Geometría releída del IFC; datum absoluto de proceso provisional","status":"derivado"}]} | {"documentId":"LHD2609-JG00100-20260904","title":"Cimentaciones de equipos y pedestales del fabricante · revisión recibida 04/09/2026","date":"2026-09-04","sheet":"2–2","fileName":"LHD2609-JG00100_20260904.dwg","revisionCaveat":"Fecha de revisión tomada del nombre recibido; cajetines internos mantienen 02/07/2026 y algunos textos de plantilla.","sourceFileSha256":"b42eb027b7bc0b14c38d1d13514f4899b58a732aa8d0ba2ccf10fa2fc3192890"} | provisional | ["La etiqueta inferior indica −3,000 m, pero la sección y su cadena 200 + 1000 = 1200 mm indican −1,000 m. Se adopta −1,000 m para la geometría; pendiente de aclaración del fabricante."] | {"Cota inferior relativa (m)":-1,"Cota superior relativa (m)":0.15000000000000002,"Cero absoluto de visualización (m)":286.1,"Estado del cero absoluto":"Provisional","Criterio":"Las cotas relativas proceden del dibujo; la equivalencia absoluta no está confirmada."} | {"boundingBoxM":{"min":[53.354292,62.945502,0.1],"max":[57.616664,65.669816,1.25]},"extentsM":[4.262372,2.724314,1.15],"meshSurfaceM2":31.860001,"meshVolumeM3":10.12,"closedSolid":true,"basis":"Magnitudes de las mallas representadas, no cantidades certificadas de obra, compra o fabricación. Las partes pueden compartir superficies; no se suman como un despiece de materiales."} | {"profileId":"concrete_reinforced","name":"Hormigón armado · gris natural","materialName":"Hormigón armado · clase pendiente de confirmar","physicalMaterialStatus":"Clase no confirmada en la hoja de equipo","physicalMaterialSource":"Geometría de cimentación del fabricante; no se extrapola HA-30 de la nota de pedestales.","appearanceStatus":"criterio_visual","appearanceBasis":"Interpretación visual del material documental; el acabado, tono y parámetros PBR no son una especificación contractual.","note":"La apariencia gráfica no modifica ni confirma la especificación física del material."} | {"elementId":"found_0904_8eb17fb9bfce5d","ifcGuid":"3Q3Wf583vUB9kF7KgRdOpa","ifcClass":"IfcFooting","buildingId":"process_plant","buildingName":"Zona de separación de aire","sourceDocumentId":"LHD2609-JG00100-20260904","sourceRepresentationKind":"foundation"} | {"layerId":"foundations","layerName":"Cimentaciones","role":"Cimentación industrial","basis":"Clasificación por función del elemento; no modifica las especificaciones documentales."} | {"profileId":"concrete_reinforced","name":"Hormigón armado · gris natural","status":"criterio_visual","basis":"Interpretación visual del material documental; el acabado, tono y parámetros PBR no son una especificación contractual.","physicalMaterialUnchanged":true} | 10.12 | Hormigón armado · clase pendiente de confirmar | Hormigón armado · gris natural | found_0904_8eb17fb9bfce5d | Geometría de cimentación del fabricante; no se extrapola HA-30 de la nota de pedestales. | Clase no confirmada en la hoja de equipo | concrete_reinforced | [0.666667,0.662745,0.619608] | 0.96 | Zona de separación de aire; BIM · Cimentaciones | 4.26237 | 2.72431 | 1.15 | 285.1 | 286.25 | F-RU1101B | ["RU1101B"] | [] | 2–2 | ["2933/2402","28CEA"] | F-RU1101B/Base del preenfriador RU1101B · cuerpo de hormigón | foundation | Geometría de fabricante; implantación absoluta provisional | RU1101B | Cimentaciones de equipos y pedestales del fabricante · revisión recibida 04/09/2026 | 2933/2402, 28CEA | -1 | 0.15 | 8.8 | Cotas relativas del dibujo. La equivalencia con un datum absoluto está pendiente. | Z del modelo = cota relativa + 1,10 m. Correspondencia provisional con 286,10 m; no es cota de obra confirmada. | Sección y contornos del fabricante; incidencias conservadas | 4 | 2.2 | La etiqueta inferior indica −3,000 m, pero la sección y su cadena 200 + 1000 = 1200 mm indican −1,000 m. Se adopta −1,000 m para la geometría; pendiente de aclaración del fabricante.
Base del preenfriador RU1101C · cuerpo de hormigón | Parcela industrial Jinhong | Cimentación industrial | Cimentaciones de equipos y pedestales del fabricante · revisión recibida 04/09/2026 | 4.26237 | 2.72431 | 1.15 | 31.86 | 10.12 | process_plant | Zona de separación de aire | {"name":"Hormigón armado · clase pendiente de confirmar","status":"Clase no confirmada en la hoja de equipo","source":"Geometría de cimentación del fabricante; no se extrapola HA-30 de la nota de pedestales."} | {"documented":[{"label":"Extensión local X","value":4.0,"unit":"m","source":"23FF/2402, 28CEA","status":"derivada del contorno CAD"},{"label":"Extensión local Y","value":2.2,"unit":"m","source":"23FF/2402, 28CEA","status":"derivada del contorno CAD"},{"label":"Cota inferior relativa adoptada","value":-1,"unit":"m","source":"2–2","status":"interpretación con conflicto conservado"},{"label":"Cota superior relativa adoptada","value":0.15000000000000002,"unit":"m","source":"2–2","status":"documentada / separación por material"}],"geometry":[{"label":"Extensión de la malla en X","value":4.262371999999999,"unit":"m","source":"Geometría releída del IFC; datum absoluto de proceso provisional","status":"derivado"},{"label":"Extensión de la malla en Y","value":2.724314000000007,"unit":"m","source":"Geometría releída del IFC; datum absoluto de proceso provisional","status":"derivado"},{"label":"Extensión de la malla en Z","value":1.15,"unit":"m","source":"Geometría releída del IFC; datum absoluto de proceso provisional","status":"derivado"},{"label":"Cota inferior de visualización","value":285.1,"unit":"m","source":"Geometría releída del IFC; datum absoluto de proceso provisional","status":"derivado"},{"label":"Cota superior de visualización","value":286.25,"unit":"m","source":"Geometría releída del IFC; datum absoluto de proceso provisional","status":"derivado"}]} | {"documentId":"LHD2609-JG00100-20260904","title":"Cimentaciones de equipos y pedestales del fabricante · revisión recibida 04/09/2026","date":"2026-09-04","sheet":"2–2","fileName":"LHD2609-JG00100_20260904.dwg","revisionCaveat":"Fecha de revisión tomada del nombre recibido; cajetines internos mantienen 02/07/2026 y algunos textos de plantilla.","sourceFileSha256":"b42eb027b7bc0b14c38d1d13514f4899b58a732aa8d0ba2ccf10fa2fc3192890"} | provisional | ["La etiqueta inferior indica −3,000 m, pero la sección y su cadena 200 + 1000 = 1200 mm indican −1,000 m. Se adopta −1,000 m para la geometría; pendiente de aclaración del fabricante."] | {"Cota inferior relativa (m)":-1,"Cota superior relativa (m)":0.15000000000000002,"Cero absoluto de visualización (m)":286.1,"Estado del cero absoluto":"Provisional","Criterio":"Las cotas relativas proceden del dibujo; la equivalencia absoluta no está confirmada."} | {"boundingBoxM":{"min":[59.694649,62.073797,0.1],"max":[63.957021,64.798111,1.25]},"extentsM":[4.262372,2.724314,1.15],"meshSurfaceM2":31.860001,"meshVolumeM3":10.12,"closedSolid":true,"basis":"Magnitudes de las mallas representadas, no cantidades certificadas de obra, compra o fabricación. Las partes pueden compartir superficies; no se suman como un despiece de materiales."} | {"profileId":"concrete_reinforced","name":"Hormigón armado · gris natural","materialName":"Hormigón armado · clase pendiente de confirmar","physicalMaterialStatus":"Clase no confirmada en la hoja de equipo","physicalMaterialSource":"Geometría de cimentación del fabricante; no se extrapola HA-30 de la nota de pedestales.","appearanceStatus":"criterio_visual","appearanceBasis":"Interpretación visual del material documental; el acabado, tono y parámetros PBR no son una especificación contractual.","note":"La apariencia gráfica no modifica ni confirma la especificación física del material."} | {"elementId":"found_0904_9aabf738deda63","ifcGuid":"2o5D1lNQHSMhvLAjDxRE2_","ifcClass":"IfcFooting","buildingId":"process_plant","buildingName":"Zona de separación de aire","sourceDocumentId":"LHD2609-JG00100-20260904","sourceRepresentationKind":"foundation"} | {"layerId":"foundations","layerName":"Cimentaciones","role":"Cimentación industrial","basis":"Clasificación por función del elemento; no modifica las especificaciones documentales."} | {"profileId":"concrete_reinforced","name":"Hormigón armado · gris natural","status":"criterio_visual","basis":"Interpretación visual del material documental; el acabado, tono y parámetros PBR no son una especificación contractual.","physicalMaterialUnchanged":true} | 10.12 | Hormigón armado · clase pendiente de confirmar | Hormigón armado · gris natural | found_0904_9aabf738deda63 | Geometría de cimentación del fabricante; no se extrapola HA-30 de la nota de pedestales. | Clase no confirmada en la hoja de equipo | concrete_reinforced | [0.666667,0.662745,0.619608] | 0.96 | Zona de separación de aire; BIM · Cimentaciones | 4.26237 | 2.72431 | 1.15 | 285.1 | 286.25 | F-RU1101C | ["RU1101C"] | [] | 2–2 | ["23FF/2402","28CEA"] | F-RU1101C/Base del preenfriador RU1101C · cuerpo de hormigón | foundation | Geometría de fabricante; implantación absoluta provisional | RU1101C | Cimentaciones de equipos y pedestales del fabricante · revisión recibida 04/09/2026 | 23FF/2402, 28CEA | -1 | 0.15 | 8.8 | Cotas relativas del dibujo. La equivalencia con un datum absoluto está pendiente. | Z del modelo = cota relativa + 1,10 m. Correspondencia provisional con 286,10 m; no es cota de obra confirmada. | Sección y contornos del fabricante; incidencias conservadas | 4 | 2.2 | La etiqueta inferior indica −3,000 m, pero la sección y su cadena 200 + 1000 = 1200 mm indican −1,000 m. Se adopta −1,000 m para la geometría; pendiente de aclaración del fabricante.
Cimentación de purificación · cuerpo de hormigón | Parcela industrial Jinhong | Cimentación industrial | Cimentaciones de equipos y pedestales del fabricante · revisión recibida 04/09/2026 | 11.2255 | 8.83301 | 1.05 | 191.88 | 81.1125 | process_plant | Zona de separación de aire | {"name":"Hormigón armado · clase pendiente de confirmar","status":"Clase no confirmada en la hoja de equipo","source":"Geometría de cimentación del fabricante; no se extrapola HA-30 de la nota de pedestales."} | {"documented":[{"label":"Extensión local X","value":10.3,"unit":"m","source":"283A, 28D14, 283A/F525","status":"derivada del contorno CAD"},{"label":"Extensión local Y","value":7.5,"unit":"m","source":"283A, 28D14, 283A/F525","status":"derivada del contorno CAD"},{"label":"Cota inferior relativa adoptada","value":-1,"unit":"m","source":"3–3","status":"interpretación con conflicto conservado"},{"label":"Cota superior relativa adoptada","value":0.05,"unit":"m","source":"3–3","status":"documentada / separación por material"}],"geometry":[{"label":"Extensión de la malla en X","value":11.225541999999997,"unit":"m","source":"Geometría releída del IFC; datum absoluto de proceso provisional","status":"derivado"},{"label":"Extensión de la malla en Y","value":8.833006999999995,"unit":"m","source":"Geometría releída del IFC; datum absoluto de proceso provisional","status":"derivado"},{"label":"Extensión de la malla en Z","value":1.0499999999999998,"unit":"m","source":"Geometría releída del IFC; datum absoluto de proceso provisional","status":"derivado"},{"label":"Cota inferior de visualización","value":285.1,"unit":"m","source":"Geometría releída del IFC; datum absoluto de proceso provisional","status":"derivado"},{"label":"Cota superior de visualización","value":286.15,"unit":"m","source":"Geometría releída del IFC; datum absoluto de proceso provisional","status":"derivado"}]} | {"documentId":"LHD2609-JG00100-20260904","title":"Cimentaciones de equipos y pedestales del fabricante · revisión recibida 04/09/2026","date":"2026-09-04","sheet":"3–3","fileName":"LHD2609-JG00100_20260904.dwg","revisionCaveat":"Fecha de revisión tomada del nombre recibido; cajetines internos mantienen 02/07/2026 y algunos textos de plantilla.","sourceFileSha256":"b42eb027b7bc0b14c38d1d13514f4899b58a732aa8d0ba2ccf10fa2fc3192890"} | provisional | ["Los símbolos simplificados del plano general de apoyos no definen el alzado de los recipientes."] | {"Cota inferior relativa (m)":-1,"Cota superior relativa (m)":0.05,"Cero absoluto de visualización (m)":286.1,"Estado del cero absoluto":"Provisional","Criterio":"Las cotas relativas proceden del dibujo; la equivalencia absoluta no está confirmada."} | {"boundingBoxM":{"min":[48.280284,53.448005,0.1],"max":[59.505826,62.281012,1.15]},"extentsM":[11.225542,8.833007,1.05],"meshSurfaceM2":191.880009,"meshVolumeM3":81.112504,"closedSolid":true,"basis":"Magnitudes de las mallas representadas, no cantidades certificadas de obra, compra o fabricación. Las partes pueden compartir superficies; no se suman como un despiece de materiales."} | {"profileId":"concrete_reinforced","name":"Hormigón armado · gris natural","materialName":"Hormigón armado · clase pendiente de confirmar","physicalMaterialStatus":"Clase no confirmada en la hoja de equipo","physicalMaterialSource":"Geometría de cimentación del fabricante; no se extrapola HA-30 de la nota de pedestales.","appearanceStatus":"criterio_visual","appearanceBasis":"Interpretación visual del material documental; el acabado, tono y parámetros PBR no son una especificación contractual.","note":"La apariencia gráfica no modifica ni confirma la especificación física del material."} | {"elementId":"found_0904_a16d8875227a01","ifcGuid":"1MT3zdfZvI_euWauLOlLxO","ifcClass":"IfcFooting","buildingId":"process_plant","buildingName":"Zona de separación de aire","sourceDocumentId":"LHD2609-JG00100-20260904","sourceRepresentationKind":"foundation"} | {"layerId":"foundations","layerName":"Cimentaciones","role":"Cimentación industrial","basis":"Clasificación por función del elemento; no modifica las especificaciones documentales."} | {"profileId":"concrete_reinforced","name":"Hormigón armado · gris natural","status":"criterio_visual","basis":"Interpretación visual del material documental; el acabado, tono y parámetros PBR no son una especificación contractual.","physicalMaterialUnchanged":true} | 81.1125 | Hormigón armado · clase pendiente de confirmar | Hormigón armado · gris natural | found_0904_a16d8875227a01 | Geometría de cimentación del fabricante; no se extrapola HA-30 de la nota de pedestales. | Clase no confirmada en la hoja de equipo | concrete_reinforced | [0.666667,0.662745,0.619608] | 0.96 | Zona de separación de aire; BIM · Cimentaciones | 11.2255 | 8.83301 | 1.05 | 285.1 | 286.15 | F-PPU | ["PPU-A-PLAN","PPU-B-PLAN","HEATER-PLAN","PPU-VALVE-SKID"] | [] | 3–3 | ["283A","28D14","283A/F525"] | F-PPU/Cimentación de purificación · cuerpo de hormigón | foundation | Geometría de fabricante; implantación absoluta provisional | PPU-A-PLAN, PPU-B-PLAN, HEATER-PLAN, PPU-VALVE-SKID | Cimentaciones de equipos y pedestales del fabricante · revisión recibida 04/09/2026 | 283A, 28D14, 283A/F525 | -1 | 0.05 | 77.25 | Cotas relativas del dibujo. La equivalencia con un datum absoluto está pendiente. | Z del modelo = cota relativa + 1,10 m. Correspondencia provisional con 286,10 m; no es cota de obra confirmada. | Sección y contornos del fabricante; incidencias conservadas | 10.3 | 7.5 | Los símbolos simplificados del plano general de apoyos no definen el alzado de los recipientes.
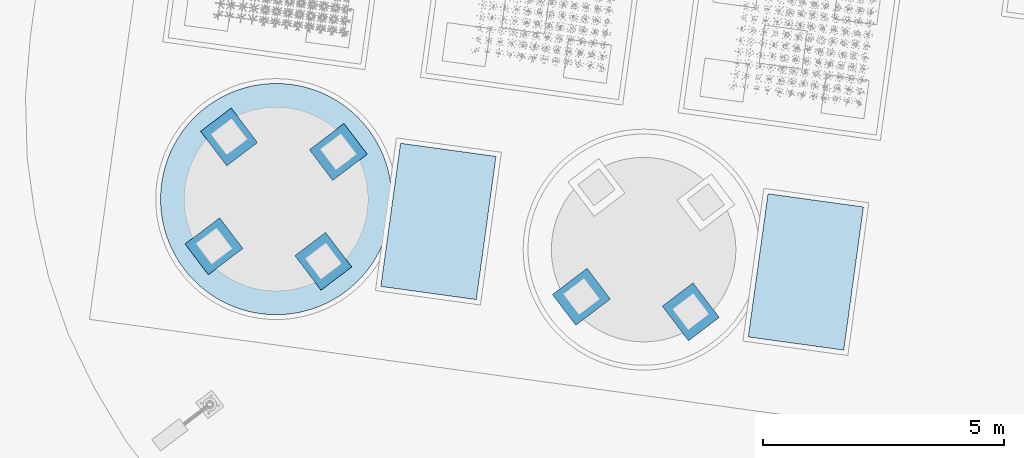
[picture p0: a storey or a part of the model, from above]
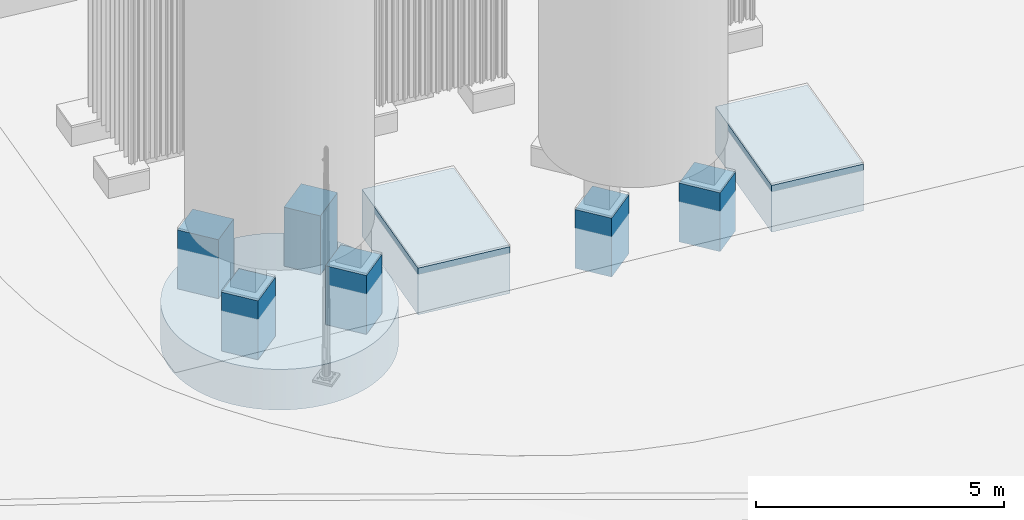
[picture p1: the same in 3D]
Properties of the parts of a building model (IFC4), part 66 of 134

# IfcFooting (214)
Name | In | Description = category = Categoria = Funcion | Document | ExtensionX (m) | ExtensionY (m) | ExtensionZ (m) | SuperficieDeLaMalla (m2) | VolumenGeometrico (m3) | buildingId | buildingName | material | dimensions | JH_InformacionBIM, source = DocumentoFuente | JH_InformacionBIM, status = EstadoDeInformacion | issues = IncidenciasPendientes | positioning = PosicionYEstado | geometryMetrics | materialAppearance | visualizationIdentity | classification | appearance | Volumen geométrico (m³) | JH_Trazabilidad, Material = name | Acabado de visualización = Acabado | Identificador | JH_EvidenciaDeMaterial, source | JH_EvidenciaDeMaterial, status | Perfil | ColorRGB | Rugosidad | Group | Extensión de la malla en X (m) | Extensión de la malla en Y (m) | Extensión de la malla en Z (m) = Espesor o altura real de sección (m) | Cota inferior de visualización (m) | Cota superior de visualización (m) | assemblyId = Conjunto de cimentación | equipmentIds | supportPositionIds | sectionRef = Sección de referencia | sourceCadHandles | stableElementKey | representationKind | geometryStatus | Equipos asociados | Documento de origen | Identificadores CAD de referencia | Cota inferior relativa (m) = Cota inferior relativa adoptada (m) | Cota superior relativa (m) = Cota superior relativa adoptada (m) | Área de planta (m²) | Referencia vertical | Implantación para visualización | Estado de la geometría | Extensión local X (m) | Extensión local Y (m) | Incidencias de origen
Cimentación de las cajas frías · cuerpo de hormigón | Parcela industrial Jinhong | Cimentación industrial | Cimentaciones de equipos y pedestales del fabricante · revisión recibida 04/09/2026 | 12.491 | 15.6328 | 1.5 | 356.152 | 208.682 | process_plant | Zona de separación de aire | {"name":"Hormigón HA-40","status":"documentado","source":"Nota de caja fría 1FCF3"} | {"documented":[{"label":"Extensión local X","value":11.29,"unit":"m","source":"240F/2420, 240F/250C, 240F/250D, 240F/250E, 240F/250F, 240F/2510, 1FCF3","status":"derivada del contorno CAD"},{"label":"Extensión local Y","value":14.68,"unit":"m","source":"240F/2420, 240F/250C, 240F/250D, 240F/250E, 240F/250F, 240F/2510, 1FCF3","status":"derivada del contorno CAD"},{"label":"Cota inferior relativa adoptada","value":-1.5,"unit":"m","source":"4–4 / 4a–4a","status":"interpretación con conflicto conservado"},{"label":"Cota superior relativa adoptada","value":0,"unit":"m","source":"4–4 / 4a–4a","status":"documentada / separación por material"}],"geometry":[{"label":"Extensión de la malla en X","value":12.490982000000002,"unit":"m","source":"Geometría releída del IFC; datum absoluto de proceso provisional","status":"derivado"},{"label":"Extensión de la malla en Y","value":15.632825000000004,"unit":"m","source":"Geometría releída del IFC; datum absoluto de proceso provisional","status":"derivado"},{"label":"Extensión de la malla en Z","value":1.5,"unit":"m","source":"Geometría releída del IFC; datum absoluto de proceso provisional","status":"derivado"},{"label":"Cota inferior de visualización","value":284.6,"unit":"m","source":"Geometría releída del IFC; datum absoluto de proceso provisional","status":"derivado"},{"label":"Cota superior de visualización","value":286.1,"unit":"m","source":"Geometría releída del IFC; datum absoluto de proceso provisional","status":"derivado"}]} | {"documentId":"LHD2609-JG00100-20260904","title":"Cimentaciones de equipos y pedestales del fabricante · revisión recibida 04/09/2026","date":"2026-09-04","sheet":"4–4 / 4a–4a","fileName":"LHD2609-JG00100_20260904.dwg","revisionCaveat":"Fecha de revisión tomada del nombre recibido; cajetines internos mantienen 02/07/2026 y algunos textos de plantilla.","sourceFileSha256":"b42eb027b7bc0b14c38d1d13514f4899b58a732aa8d0ba2ccf10fa2fc3192890"} | provisional | ["Sección 4–4: etiqueta inferior −1,000 m frente a 1500 mm. Sección 4a–4a y espesor1500 mm: −1,500 m. Se adopta −1,500 m; conflicto pendiente."] | {"Cota inferior relativa (m)":-1.5,"Cota superior relativa (m)":0,"Cero absoluto de visualización (m)":286.1,"Estado del cero absoluto":"Provisional","Criterio":"Las cotas relativas proceden del dibujo; la equivalencia absoluta no está confirmada."} | {"boundingBoxM":{"min":[48.97652,35.309988,-0.4],"max":[61.467502,50.942813,1.1]},"extentsM":[12.490982,15.632825,1.5],"meshSurfaceM2":356.152189,"meshVolumeM3":208.681643,"closedSolid":true,"basis":"Magnitudes de las mallas representadas, no cantidades certificadas de obra, compra o fabricación. Las partes pueden compartir superficies; no se suman como un despiece de materiales."} | {"profileId":"concrete_ha40","name":"Hormigón HA-40","materialName":"Hormigón HA-40","physicalMaterialStatus":"documentado","physicalMaterialSource":"Nota de caja fría 1FCF3","appearanceStatus":"criterio_visual","appearanceBasis":"Interpretación visual del material documental; el acabado, tono y parámetros PBR no son una especificación contractual.","note":"La apariencia gráfica no modifica ni confirma la especificación física del material."} | {"elementId":"found_0904_ab1632a7d9dd78","ifcGuid":"1vlPN_VyvOIwUgxVTc$ffo","ifcClass":"IfcFooting","buildingId":"process_plant","buildingName":"Zona de separación de aire","sourceDocumentId":"LHD2609-JG00100-20260904","sourceRepresentationKind":"foundation"} | {"layerId":"foundations","layerName":"Cimentaciones","role":"Cimentación industrial","basis":"Clasificación por función del elemento; no modifica las especificaciones documentales."} | {"profileId":"concrete_ha40","name":"Hormigón HA-40","status":"criterio_visual","basis":"Interpretación visual del material documental; el acabado, tono y parámetros PBR no son una especificación contractual.","physicalMaterialUnchanged":true} | 208.682 | Hormigón HA-40 | Hormigón HA-40 | found_0904_ab1632a7d9dd78 | Nota de caja fría 1FCF3 | documentado | concrete_ha40 | [0.6,0.611765,0.588235] | 0.94 | Zona de separación de aire; BIM · Cimentaciones | 12.491 | 15.6328 | 1.5 | 284.6 | 286.1 | F-CB | ["CB-MAIN","CB-HX-PLAN","CB-EXP-N-PLAN","CB-EXP-W-PLAN"] | [] | 4–4 / 4a–4a | ["240F/2420","240F/250C","240F/250D","240F/250E","240F/250F","240F/2510","1FCF3"] | F-CB/Cimentación de las cajas frías · cuerpo de hormigón | foundation | Geometría de fabricante; implantación absoluta provisional | CB-MAIN, CB-HX-PLAN, CB-EXP-N-PLAN, CB-EXP-W-PLAN | Cimentaciones de equipos y pedestales del fabricante · revisión recibida 04/09/2026 | 240F/2420, 240F/250C, 240F/250D, 240F/250E, 240F/250F, 240F/2510, 1FCF3 | -1.5 | 0 | 139.121 | Cotas relativas del dibujo. La equivalencia con un datum absoluto está pendiente. | Z del modelo = cota relativa + 1,10 m. Correspondencia provisional con 286,10 m; no es cota de obra confirmada. | Sección y contornos del fabricante; incidencias conservadas | 11.29 | 14.68 | Sección 4–4: etiqueta inferior −1,000 m frente a 1500 mm. Sección 4a–4a y espesor1500 mm: −1,500 m. Se adopta −1,500 m; conflicto pendiente. | Material: Hormigón HA-40; JH_InformacionBIM - conceptualReferenceIds: ["CB-HX-CONCEPT","CB-EXP-N-CONCEPT","CB-EXP-W-CONCEPT"]; JH_ReferenciasDeEsquema - ObjetosIlustrativos: ["CB-HX-CONCEPT","CB-EXP-N-CONCEPT","CB-EXP-W-CONCEPT"]; Nota: Relación de visualización, no conexión de montaje aprobada.
Cimentación de las cajas frías · plataforma irregular elevada 100 mm | Parcela industrial Jinhong | Cimentación industrial | Cimentaciones de equipos y pedestales del fabricante · revisión recibida 04/09/2026 | 10.5096 | 13.3791 | 0.1 | 199.916 | 9.77611 | process_plant | Zona de separación de aire | {"name":"Hormigón HA-40","status":"documentado","source":"Nota de caja fría 1FCF3"} | {"documented":[{"label":"Extensión local X","value":9.29,"unit":"m","source":"240F/2420, 240F/250C, 240F/250D, 240F/250E, 240F/250F, 240F/2510, 1FCF3","status":"derivada del contorno CAD"},{"label":"Extensión local Y","value":12.68,"unit":"m","source":"240F/2420, 240F/250C, 240F/250D, 240F/250E, 240F/250F, 240F/2510, 1FCF3","status":"derivada del contorno CAD"},{"label":"Cota inferior relativa adoptada","value":0,"unit":"m","source":"4–4 / 4a–4a","status":"interpretación con conflicto conservado"},{"label":"Cota superior relativa adoptada","value":0.1,"unit":"m","source":"4–4 / 4a–4a","status":"documentada / separación por material"}],"geometry":[{"label":"Extensión de la malla en X","value":10.509619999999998,"unit":"m","source":"Geometría releída del IFC; datum absoluto de proceso provisional","status":"derivado"},{"label":"Extensión de la malla en Y","value":13.379055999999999,"unit":"m","source":"Geometría releída del IFC; datum absoluto de proceso provisional","status":"derivado"},{"label":"Extensión de la malla en Z","value":0.09999999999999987,"unit":"m","source":"Geometría releída del IFC; datum absoluto de proceso provisional","status":"derivado"},{"label":"Cota inferior de visualización","value":286.1,"unit":"m","source":"Geometría releída del IFC; datum absoluto de proceso provisional","status":"derivado"},{"label":"Cota superior de visualización","value":286.2,"unit":"m","source":"Geometría releída del IFC; datum absoluto de proceso provisional","status":"derivado"}]} | {"documentId":"LHD2609-JG00100-20260904","title":"Cimentaciones de equipos y pedestales del fabricante · revisión recibida 04/09/2026","date":"2026-09-04","sheet":"4–4 / 4a–4a","fileName":"LHD2609-JG00100_20260904.dwg","revisionCaveat":"Fecha de revisión tomada del nombre recibido; cajetines internos mantienen 02/07/2026 y algunos textos de plantilla.","sourceFileSha256":"b42eb027b7bc0b14c38d1d13514f4899b58a732aa8d0ba2ccf10fa2fc3192890"} | provisional | ["Sección 4–4: etiqueta inferior −1,000 m frente a 1500 mm. Sección 4a–4a y espesor1500 mm: −1,500 m. Se adopta −1,500 m; conflicto pendiente."] | {"Cota inferior relativa (m)":0,"Cota superior relativa (m)":0.1,"Cero absoluto de visualización (m)":286.1,"Estado del cero absoluto":"Provisional","Criterio":"Las cotas relativas proceden del dibujo; la equivalencia absoluta no está confirmada."} | {"boundingBoxM":{"min":[48.97652,37.563757,1.1],"max":[59.48614,50.942813,1.2]},"extentsM":[10.50962,13.379056,0.1],"meshSurfaceM2":199.916182,"meshVolumeM3":9.776109,"closedSolid":true,"basis":"Magnitudes de las mallas representadas, no cantidades certificadas de obra, compra o fabricación. Las partes pueden compartir superficies; no se suman como un despiece de materiales."} | {"profileId":"concrete_ha40","name":"Hormigón HA-40","materialName":"Hormigón HA-40","physicalMaterialStatus":"documentado","physicalMaterialSource":"Nota de caja fría 1FCF3","appearanceStatus":"criterio_visual","appearanceBasis":"Interpretación visual del material documental; el acabado, tono y parámetros PBR no son una especificación contractual.","note":"La apariencia gráfica no modifica ni confirma la especificación física del material."} | {"elementId":"found_0904_e82a8a5ec7336e","ifcGuid":"3ut7opQxDUdQqTYm4bqd5a","ifcClass":"IfcFooting","buildingId":"process_plant","buildingName":"Zona de separación de aire","sourceDocumentId":"LHD2609-JG00100-20260904","sourceRepresentationKind":"foundation"} | {"layerId":"foundations","layerName":"Cimentaciones","role":"Cimentación industrial","basis":"Clasificación por función del elemento; no modifica las especificaciones documentales."} | {"profileId":"concrete_ha40","name":"Hormigón HA-40","status":"criterio_visual","basis":"Interpretación visual del material documental; el acabado, tono y parámetros PBR no son una especificación contractual.","physicalMaterialUnchanged":true} | 9.77611 | Hormigón HA-40 | Hormigón HA-40 | found_0904_e82a8a5ec7336e | Nota de caja fría 1FCF3 | documentado | concrete_ha40 | [0.6,0.611765,0.588235] | 0.94 | Zona de separación de aire; BIM · Cimentaciones | 10.5096 | 13.3791 | 0.1 | 286.1 | 286.2 | F-CB | ["CB-MAIN","CB-HX-PLAN","CB-EXP-N-PLAN","CB-EXP-W-PLAN"] | [] | 4–4 / 4a–4a | ["240F/2420","240F/250C","240F/250D","240F/250E","240F/250F","240F/2510","1FCF3"] | F-CB/Cimentación de las cajas frías · plataforma irregular elevada 100 mm | foundation | Geometría de fabricante; implantación absoluta provisional | CB-MAIN, CB-HX-PLAN, CB-EXP-N-PLAN, CB-EXP-W-PLAN | Cimentaciones de equipos y pedestales del fabricante · revisión recibida 04/09/2026 | 240F/2420, 240F/250C, 240F/250D, 240F/250E, 240F/250F, 240F/2510, 1FCF3 | 0 | 0.1 | 97.7611 | Cotas relativas del dibujo. La equivalencia con un datum absoluto está pendiente. | Z del modelo = cota relativa + 1,10 m. Correspondencia provisional con 286,10 m; no es cota de obra confirmada. | Sección y contornos del fabricante; incidencias conservadas | 9.29 | 12.68 | Sección 4–4: etiqueta inferior −1,000 m frente a 1500 mm. Sección 4a–4a y espesor1500 mm: −1,500 m. Se adopta −1,500 m; conflicto pendiente. | Material: Hormigón HA-40; JH_InformacionBIM - conceptualReferenceIds: ["CB-HX-CONCEPT","CB-EXP-N-CONCEPT","CB-EXP-W-CONCEPT"]; JH_ReferenciasDeEsquema - ObjetosIlustrativos: ["CB-HX-CONCEPT","CB-EXP-N-CONCEPT","CB-EXP-W-CONCEPT"]; Nota: Relación de visualización, no conexión de montaje aprobada.
Cimentación del evaporador de residuos · apoyo rectangular · cuerpo de hormigón | Parcela industrial Jinhong | Cimentación industrial | Cimentaciones de equipos y pedestales del fabricante · revisión recibida 04/09/2026 | 1.75535 | 1.0675 | 1.67 | 11.1802 | 2.34927 | process_plant | Zona de separación de aire | {"name":"Hormigón armado · clase pendiente de confirmar","status":"Clase no confirmada en la hoja de equipo","source":"Geometría de cimentación del fabricante; no se extrapola HA-30 de la nota de pedestales."} | {"documented":[{"label":"Extensión local X","value":1.655,"unit":"m","source":"2516/2530, 2516/2520, 28CA5","status":"derivada del contorno CAD"},{"label":"Extensión local Y","value":0.85,"unit":"m","source":"2516/2530, 2516/2520, 28CA5","status":"derivada del contorno CAD"},{"label":"Cota inferior relativa adoptada","value":-1,"unit":"m","source":"5–5","status":"interpretación con conflicto conservado"},{"label":"Cota superior relativa adoptada","value":0.6699999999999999,"unit":"m","source":"5–5","status":"documentada / separación por material"}],"geometry":[{"label":"Extensión de la malla en X","value":1.75535,"unit":"m","source":"Geometría releída del IFC; datum absoluto de proceso provisional","status":"derivado"},{"label":"Extensión de la malla en Y","value":1.0674959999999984,"unit":"m","source":"Geometría releída del IFC; datum absoluto de proceso provisional","status":"derivado"},{"label":"Extensión de la malla en Z","value":1.67,"unit":"m","source":"Geometría releída del IFC; datum absoluto de proceso provisional","status":"derivado"},{"label":"Cota inferior de visualización","value":285.1,"unit":"m","source":"Geometría releída del IFC; datum absoluto de proceso provisional","status":"derivado"},{"label":"Cota superior de visualización","value":286.77,"unit":"m","source":"Geometría releída del IFC; datum absoluto de proceso provisional","status":"derivado"}]} | {"documentId":"LHD2609-JG00100-20260904","title":"Cimentaciones de equipos y pedestales del fabricante · revisión recibida 04/09/2026","date":"2026-09-04","sheet":"5–5","fileName":"LHD2609-JG00100_20260904.dwg","revisionCaveat":"Fecha de revisión tomada del nombre recibido; cajetines internos mantienen 02/07/2026 y algunos textos de plantilla.","sourceFileSha256":"b42eb027b7bc0b14c38d1d13514f4899b58a732aa8d0ba2ccf10fa2fc3192890"} | provisional | ["La longitud de la base rectangular varía entre la planta y la cadena de cotas de sección. Se conserva el contorno CAD general de 1,655 × 0,850 m."] | {"Cota inferior relativa (m)":-1,"Cota superior relativa (m)":0.6699999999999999,"Cero absoluto de visualización (m)":286.1,"Estado del cero absoluto":"Provisional","Criterio":"Las cotas relativas proceden del dibujo; la equivalencia absoluta no está confirmada."} | {"boundingBoxM":{"min":[48.388285,38.788323,0.1],"max":[50.143635,39.855819,1.77]},"extentsM":[1.75535,1.067496,1.67],"meshSurfaceM2":11.1802,"meshVolumeM3":2.349272,"closedSolid":true,"basis":"Magnitudes de las mallas representadas, no cantidades certificadas de obra, compra o fabricación. Las partes pueden compartir superficies; no se suman como un despiece de materiales."} | {"profileId":"concrete_reinforced","name":"Hormigón armado · gris natural","materialName":"Hormigón armado · clase pendiente de confirmar","physicalMaterialStatus":"Clase no confirmada en la hoja de equipo","physicalMaterialSource":"Geometría de cimentación del fabricante; no se extrapola HA-30 de la nota de pedestales.","appearanceStatus":"criterio_visual","appearanceBasis":"Interpretación visual del material documental; el acabado, tono y parámetros PBR no son una especificación contractual.","note":"La apariencia gráfica no modifica ni confirma la especificación física del material."} | {"elementId":"found_0904_40426c0d432102","ifcGuid":"2TlXApR_HNJx9xC0uBV5gn","ifcClass":"IfcFooting","buildingId":"process_plant","buildingName":"Zona de separación de aire","sourceDocumentId":"LHD2609-JG00100-20260904","sourceRepresentationKind":"foundation"} | {"layerId":"foundations","layerName":"Cimentaciones","role":"Cimentación industrial","basis":"Clasificación por función del elemento; no modifica las especificaciones documentales."} | {"profileId":"concrete_reinforced","name":"Hormigón armado · gris natural","status":"criterio_visual","basis":"Interpretación visual del material documental; el acabado, tono y parámetros PBR no son una especificación contractual.","physicalMaterialUnchanged":true} | 2.34927 | Hormigón armado · clase pendiente de confirmar | Hormigón armado · gris natural | found_0904_40426c0d432102 | Geometría de cimentación del fabricante; no se extrapola HA-30 de la nota de pedestales. | Clase no confirmada en la hoja de equipo | concrete_reinforced | [0.666667,0.662745,0.619608] | 0.96 | Zona de separación de aire; BIM · Cimentaciones | 1.75535 | 1.0675 | 1.67 | 285.1 | 286.77 | F-RESIDUAL | [] | [] | 5–5 | ["2516/2530","2516/2520","28CA5"] | F-RESIDUAL/Cimentación del evaporador de residuos · apoyo rectangular · cuerpo de hormigón | foundation | Geometría de fabricante; implantación absoluta provisional |  | Cimentaciones de equipos y pedestales del fabricante · revisión recibida 04/09/2026 | 2516/2530, 2516/2520, 28CA5 | -1 | 0.67 | 1.40675 | Cotas relativas del dibujo. La equivalencia con un datum absoluto está pendiente. | Z del modelo = cota relativa + 1,10 m. Correspondencia provisional con 286,10 m; no es cota de obra confirmada. | Sección y contornos del fabricante; incidencias conservadas | 1.655 | 0.85 | La longitud de la base rectangular varía entre la planta y la cadena de cotas de sección. Se conserva el contorno CAD general de 1,655 × 0,850 m.
Cimentación del evaporador de residuos · apoyo circular · cuerpo de hormigón | Parcela industrial Jinhong | Cimentación industrial | Cimentaciones de equipos y pedestales del fabricante · revisión recibida 04/09/2026 | 1.09998 | 1.09998 | 1.15 | 5.87426 | 1.09269 | process_plant | Zona de separación de aire | {"name":"Hormigón armado · clase pendiente de confirmar","status":"Clase no confirmada en la hoja de equipo","source":"Geometría de cimentación del fabricante; no se extrapola HA-30 de la nota de pedestales."} | {"documented":[{"label":"Extensión local X","value":1.1,"unit":"m","source":"2516/2530, 2516/2520, 28CA5","status":"derivada del contorno CAD"},{"label":"Extensión local Y","value":1.1,"unit":"m","source":"2516/2530, 2516/2520, 28CA5","status":"derivada del contorno CAD"},{"label":"Cota inferior relativa adoptada","value":-1,"unit":"m","source":"5–5","status":"interpretación con conflicto conservado"},{"label":"Cota superior relativa adoptada","value":0.15000000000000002,"unit":"m","source":"5–5","status":"documentada / separación por material"}],"geometry":[{"label":"Extensión de la malla en X","value":1.0999809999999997,"unit":"m","source":"Geometría releída del IFC; datum absoluto de proceso provisional","status":"derivado"},{"label":"Extensión de la malla en Y","value":1.0999820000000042,"unit":"m","source":"Geometría releída del IFC; datum absoluto de proceso provisional","status":"derivado"},{"label":"Extensión de la malla en Z","value":1.15,"unit":"m","source":"Geometría releída del IFC; datum absoluto de proceso provisional","status":"derivado"},{"label":"Cota inferior de visualización","value":285.1,"unit":"m","source":"Geometría releída del IFC; datum absoluto de proceso provisional","status":"derivado"},{"label":"Cota superior de visualización","value":286.25,"unit":"m","source":"Geometría releída del IFC; datum absoluto de proceso provisional","status":"derivado"}]} | {"documentId":"LHD2609-JG00100-20260904","title":"Cimentaciones de equipos y pedestales del fabricante · revisión recibida 04/09/2026","date":"2026-09-04","sheet":"5–5","fileName":"LHD2609-JG00100_20260904.dwg","revisionCaveat":"Fecha de revisión tomada del nombre recibido; cajetines internos mantienen 02/07/2026 y algunos textos de plantilla.","sourceFileSha256":"b42eb027b7bc0b14c38d1d13514f4899b58a732aa8d0ba2ccf10fa2fc3192890"} | provisional | ["La longitud de la base rectangular varía entre la planta y la cadena de cotas de sección. Se conserva el contorno CAD general de 1,655 × 0,850 m."] | {"Cota inferior relativa (m)":-1,"Cota superior relativa (m)":0.15000000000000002,"Cero absoluto de visualización (m)":286.1,"Estado del cero absoluto":"Provisional","Criterio":"Las cotas relativas proceden del dibujo; la equivalencia absoluta no está confirmada."} | {"boundingBoxM":{"min":[50.359013,38.546186,0.1],"max":[51.458994,39.646168,1.25]},"extentsM":[1.099981,1.099982,1.15],"meshSurfaceM2":5.874261,"meshVolumeM3":1.092686,"closedSolid":true,"basis":"Magnitudes de las mallas representadas, no cantidades certificadas de obra, compra o fabricación. Las partes pueden compartir superficies; no se suman como un despiece de materiales."} | {"profileId":"concrete_reinforced","name":"Hormigón armado · gris natural","materialName":"Hormigón armado · clase pendiente de confirmar","physicalMaterialStatus":"Clase no confirmada en la hoja de equipo","physicalMaterialSource":"Geometría de cimentación del fabricante; no se extrapola HA-30 de la nota de pedestales.","appearanceStatus":"criterio_visual","appearanceBasis":"Interpretación visual del material documental; el acabado, tono y parámetros PBR no son una especificación contractual.","note":"La apariencia gráfica no modifica ni confirma la especificación física del material."} | {"elementId":"found_0904_2219a1d81a6934","ifcGuid":"2UmTJ4JPzPyQVVmCHMLjc1","ifcClass":"IfcFooting","buildingId":"process_plant","buildingName":"Zona de separación de aire","sourceDocumentId":"LHD2609-JG00100-20260904","sourceRepresentationKind":"foundation"} | {"layerId":"foundations","layerName":"Cimentaciones","role":"Cimentación industrial","basis":"Clasificación por función del elemento; no modifica las especificaciones documentales."} | {"profileId":"concrete_reinforced","name":"Hormigón armado · gris natural","status":"criterio_visual","basis":"Interpretación visual del material documental; el acabado, tono y parámetros PBR no son una especificación contractual.","physicalMaterialUnchanged":true} | 1.09269 | Hormigón armado · clase pendiente de confirmar | Hormigón armado · gris natural | found_0904_2219a1d81a6934 | Geometría de cimentación del fabricante; no se extrapola HA-30 de la nota de pedestales. | Clase no confirmada en la hoja de equipo | concrete_reinforced | [0.666667,0.662745,0.619608] | 0.96 | Zona de separación de aire; BIM · Cimentaciones | 1.09998 | 1.09998 | 1.15 | 285.1 | 286.25 | F-RESIDUAL | [] | [] | 5–5 | ["2516/2530","2516/2520","28CA5"] | F-RESIDUAL/Cimentación del evaporador de residuos · apoyo circular · cuerpo de hormigón | foundation | Geometría de fabricante; implantación absoluta provisional |  | Cimentaciones de equipos y pedestales del fabricante · revisión recibida 04/09/2026 | 2516/2530, 2516/2520, 28CA5 | -1 | 0.15 | 0.950162 | Cotas relativas del dibujo. La equivalencia con un datum absoluto está pendiente. | Z del modelo = cota relativa + 1,10 m. Correspondencia provisional con 286,10 m; no es cota de obra confirmada. | Sección y contornos del fabricante; incidencias conservadas | 1.1 | 1.1 | La longitud de la base rectangular varía entre la planta y la cadena de cotas de sección. Se conserva el contorno CAD general de 1,655 × 0,850 m.
Cimentación del posenfriador WE441-PLAN · cuerpo de hormigón | Parcela industrial Jinhong | Cimentación industrial | Cimentaciones de equipos y pedestales del fabricante · revisión recibida 04/09/2026 | 1.31757 | 2.51384 | 0.8 | 10.24 | 1.92 | process_plant | Zona de separación de aire | {"name":"Hormigón armado · clase pendiente de confirmar","status":"Clase no confirmada en la hoja de equipo","source":"Geometría de cimentación del fabricante; no se extrapola HA-30 de la nota de pedestales."} | {"documented":[{"label":"Extensión local X","value":1.0,"unit":"m","source":"433C/27BC, 433C/27BD, 433C/E6A3, 28D71","status":"derivada del contorno CAD"},{"label":"Extensión local Y","value":2.4,"unit":"m","source":"433C/27BC, 433C/27BD, 433C/E6A3, 28D71","status":"derivada del contorno CAD"},{"label":"Cota inferior relativa adoptada","value":-2,"unit":"m","source":"6–6","status":"interpretación con conflicto conservado"},{"label":"Cota superior relativa adoptada","value":-1.2,"unit":"m","source":"6–6","status":"documentada / separación por material"}],"geometry":[{"label":"Extensión de la malla en X","value":1.317571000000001,"unit":"m","source":"Geometría releída del IFC; datum absoluto de proceso provisional","status":"derivado"},{"label":"Extensión de la malla en Y","value":2.513838,"unit":"m","source":"Geometría releída del IFC; datum absoluto de proceso provisional","status":"derivado"},{"label":"Extensión de la malla en Z","value":0.8,"unit":"m","source":"Geometría releída del IFC; datum absoluto de proceso provisional","status":"derivado"},{"label":"Cota inferior de visualización","value":284.1,"unit":"m","source":"Geometría releída del IFC; datum absoluto de proceso provisional","status":"derivado"},{"label":"Cota superior de visualización","value":284.9,"unit":"m","source":"Geometría releída del IFC; datum absoluto de proceso provisional","status":"derivado"}]} | {"documentId":"LHD2609-JG00100-20260904","title":"Cimentaciones de equipos y pedestales del fabricante · revisión recibida 04/09/2026","date":"2026-09-04","sheet":"6–6","fileName":"LHD2609-JG00100_20260904.dwg","revisionCaveat":"Fecha de revisión tomada del nombre recibido; cajetines internos mantienen 02/07/2026 y algunos textos de plantilla.","sourceFileSha256":"b42eb027b7bc0b14c38d1d13514f4899b58a732aa8d0ba2ccf10fa2fc3192890"} | provisional | ["Planta: −2,200 m. Sección 6–6: fondo −2,000 m y coronación de losa −1,200 m. Se adopta sección; pendiente de aclaración."] | {"Cota inferior relativa (m)":-2,"Cota superior relativa (m)":-1.2,"Cero absoluto de visualización (m)":286.1,"Estado del cero absoluto":"Provisional","Criterio":"Las cotas relativas proceden del dibujo; la equivalencia absoluta no está confirmada."} | {"boundingBoxM":{"min":[46.269973,47.067517,-0.9],"max":[47.587544,49.581355,-0.1]},"extentsM":[1.317571,2.513838,0.8],"meshSurfaceM2":10.240002,"meshVolumeM3":1.92,"closedSolid":true,"basis":"Magnitudes de las mallas representadas, no cantidades certificadas de obra, compra o fabricación. Las partes pueden compartir superficies; no se suman como un despiece de materiales."} | {"profileId":"concrete_reinforced","name":"Hormigón armado · gris natural","materialName":"Hormigón armado · clase pendiente de confirmar","physicalMaterialStatus":"Clase no confirmada en la hoja de equipo","physicalMaterialSource":"Geometría de cimentación del fabricante; no se extrapola HA-30 de la nota de pedestales.","appearanceStatus":"criterio_visual","appearanceBasis":"Interpretación visual del material documental; el acabado, tono y parámetros PBR no son una especificación contractual.","note":"La apariencia gráfica no modifica ni confirma la especificación física del material."} | {"elementId":"found_0904_c9340bf51f56b7","ifcGuid":"0gxTO6hVTLsfT4c9KyBSYZ","ifcClass":"IfcFooting","buildingId":"process_plant","buildingName":"Zona de separación de aire","sourceDocumentId":"LHD2609-JG00100-20260904","sourceRepresentationKind":"foundation"} | {"layerId":"foundations","layerName":"Cimentaciones","role":"Cimentación industrial","basis":"Clasificación por función del elemento; no modifica las especificaciones documentales."} | {"profileId":"concrete_reinforced","name":"Hormigón armado · gris natural","status":"criterio_visual","basis":"Interpretación visual del material documental; el acabado, tono y parámetros PBR no son una especificación contractual.","physicalMaterialUnchanged":true} | 1.92 | Hormigón armado · clase pendiente de confirmar | Hormigón armado · gris natural | found_0904_c9340bf51f56b7 | Geometría de cimentación del fabricante; no se extrapola HA-30 de la nota de pedestales. | Clase no confirmada en la hoja de equipo | concrete_reinforced | [0.666667,0.662745,0.619608] | 0.96 | Zona de separación de aire; BIM · Cimentaciones | 1.31757 | 2.51384 | 0.8 | 284.1 | 284.9 | F-WE441-PLAN | ["WE441-PLAN"] | [] | 6–6 | ["433C/27BC","433C/27BD","433C/E6A3","28D71"] | F-WE441-PLAN/Cimentación del posenfriador WE441-PLAN · cuerpo de hormigón | foundation | Geometría de fabricante; implantación absoluta provisional | WE441-PLAN | Cimentaciones de equipos y pedestales del fabricante · revisión recibida 04/09/2026 | 433C/27BC, 433C/27BD, 433C/E6A3, 28D71 | -2 | -1.2 | 2.4 | Cotas relativas del dibujo. La equivalencia con un datum absoluto está pendiente. | Z del modelo = cota relativa + 1,10 m. Correspondencia provisional con 286,10 m; no es cota de obra confirmada. | Sección y contornos del fabricante; incidencias conservadas | 1 | 2.4 | Planta: −2,200 m. Sección 6–6: fondo −2,000 m y coronación de losa −1,200 m. Se adopta sección; pendiente de aclaración.
Cimentación del posenfriador WE441-PLAN · pedestal DZ6 1 | Parcela industrial Jinhong | Cimentación industrial | Cimentaciones de equipos y pedestales del fabricante · revisión recibida 04/09/2026 | 0.635269 | 0.378926 | 1.35 | 2.79 | 0.243 | process_plant | Zona de separación de aire | {"name":"Hormigón armado · clase pendiente de confirmar","status":"Clase no confirmada en la hoja de equipo","source":"Geometría de cimentación del fabricante; no se extrapola HA-30 de la nota de pedestales."} | {"documented":[{"label":"Extensión local X","value":0.6,"unit":"m","source":"433C/27BC, 433C/27BD, 433C/E6A3, 28D71","status":"derivada del contorno CAD"},{"label":"Extensión local Y","value":0.3,"unit":"m","source":"433C/27BC, 433C/27BD, 433C/E6A3, 28D71","status":"derivada del contorno CAD"},{"label":"Cota inferior relativa adoptada","value":-1.2,"unit":"m","source":"6–6","status":"interpretación con conflicto conservado"},{"label":"Cota superior relativa adoptada","value":0.15,"unit":"m","source":"6–6","status":"documentada / separación por material"}],"geometry":[{"label":"Extensión de la malla en X","value":0.635269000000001,"unit":"m","source":"Geometría releída del IFC; datum absoluto de proceso provisional","status":"derivado"},{"label":"Extensión de la malla en Y","value":0.3789259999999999,"unit":"m","source":"Geometría releída del IFC; datum absoluto de proceso provisional","status":"derivado"},{"label":"Extensión de la malla en Z","value":1.35,"unit":"m","source":"Geometría releída del IFC; datum absoluto de proceso provisional","status":"derivado"},{"label":"Cota inferior de visualización","value":284.9,"unit":"m","source":"Geometría releída del IFC; datum absoluto de proceso provisional","status":"derivado"},{"label":"Cota superior de visualización","value":286.25,"unit":"m","source":"Geometría releída del IFC; datum absoluto de proceso provisional","status":"derivado"}]} | {"documentId":"LHD2609-JG00100-20260904","title":"Cimentaciones de equipos y pedestales del fabricante · revisión recibida 04/09/2026","date":"2026-09-04","sheet":"6–6","fileName":"LHD2609-JG00100_20260904.dwg","revisionCaveat":"Fecha de revisión tomada del nombre recibido; cajetines internos mantienen 02/07/2026 y algunos textos de plantilla.","sourceFileSha256":"b42eb027b7bc0b14c38d1d13514f4899b58a732aa8d0ba2ccf10fa2fc3192890"} | provisional | ["Planta: −2,200 m. Sección 6–6: fondo −2,000 m y coronación de losa −1,200 m. Se adopta sección; pendiente de aclaración."] | {"Cota inferior relativa (m)":-1.2,"Cota superior relativa (m)":0.15,"Cero absoluto de visualización (m)":286.1,"Estado del cero absoluto":"Provisional","Criterio":"Las cotas relativas proceden del dibujo; la equivalencia absoluta no está confirmada."} | {"boundingBoxM":{"min":[46.713277,48.877984,-0.1],"max":[47.348546,49.25691,1.25]},"extentsM":[0.635269,0.378926,1.35],"meshSurfaceM2":2.789997,"meshVolumeM3":0.243,"closedSolid":true,"basis":"Magnitudes de las mallas representadas, no cantidades certificadas de obra, compra o fabricación. Las partes pueden compartir superficies; no se suman como un despiece de materiales."} | {"profileId":"concrete_reinforced","name":"Hormigón armado · gris natural","materialName":"Hormigón armado · clase pendiente de confirmar","physicalMaterialStatus":"Clase no confirmada en la hoja de equipo","physicalMaterialSource":"Geometría de cimentación del fabricante; no se extrapola HA-30 de la nota de pedestales.","appearanceStatus":"criterio_visual","appearanceBasis":"Interpretación visual del material documental; el acabado, tono y parámetros PBR no son una especificación contractual.","note":"La apariencia gráfica no modifica ni confirma la especificación física del material."} | {"elementId":"found_0904_bca3cc43b8eae3","ifcGuid":"2ayV_FkUPK5OadaB_ZTJIo","ifcClass":"IfcFooting","buildingId":"process_plant","buildingName":"Zona de separación de aire","sourceDocumentId":"LHD2609-JG00100-20260904","sourceRepresentationKind":"foundation"} | {"layerId":"foundations","layerName":"Cimentaciones","role":"Cimentación industrial","basis":"Clasificación por función del elemento; no modifica las especificaciones documentales."} | {"profileId":"concrete_reinforced","name":"Hormigón armado · gris natural","status":"criterio_visual","basis":"Interpretación visual del material documental; el acabado, tono y parámetros PBR no son una especificación contractual.","physicalMaterialUnchanged":true} | 0.243 | Hormigón armado · clase pendiente de confirmar | Hormigón armado · gris natural | found_0904_bca3cc43b8eae3 | Geometría de cimentación del fabricante; no se extrapola HA-30 de la nota de pedestales. | Clase no confirmada en la hoja de equipo | concrete_reinforced | [0.666667,0.662745,0.619608] | 0.96 | Zona de separación de aire; BIM · Cimentaciones | 0.635269 | 0.378926 | 1.35 | 284.9 | 286.25 | F-WE441-PLAN | ["WE441-PLAN"] | [] | 6–6 | ["433C/27BC","433C/27BD","433C/E6A3","28D71"] | F-WE441-PLAN/Cimentación del posenfriador WE441-PLAN · pedestal DZ6 1 | foundation | Geometría de fabricante; implantación absoluta provisional | WE441-PLAN | Cimentaciones de equipos y pedestales del fabricante · revisión recibida 04/09/2026 | 433C/27BC, 433C/27BD, 433C/E6A3, 28D71 | -1.2 | 0.15 | 0.18 | Cotas relativas del dibujo. La equivalencia con un datum absoluto está pendiente. | Z del modelo = cota relativa + 1,10 m. Correspondencia provisional con 286,10 m; no es cota de obra confirmada. | Sección y contornos del fabricante; incidencias conservadas | 0.6 | 0.3 | Planta: −2,200 m. Sección 6–6: fondo −2,000 m y coronación de losa −1,200 m. Se adopta sección; pendiente de aclaración.
Cimentación del posenfriador WE441-PLAN · pedestal DZ6 2 | Parcela industrial Jinhong | Cimentación industrial | Cimentaciones de equipos y pedestales del fabricante · revisión recibida 04/09/2026 | 0.635269 | 0.378927 | 1.35 | 2.79 | 0.243 | process_plant | Zona de separación de aire | {"name":"Hormigón armado · clase pendiente de confirmar","status":"Clase no confirmada en la hoja de equipo","source":"Geometría de cimentación del fabricante; no se extrapola HA-30 de la nota de pedestales."} | {"documented":[{"label":"Extensión local X","value":0.6,"unit":"m","source":"433C/27BC, 433C/27BD, 433C/E6A3, 28D71","status":"derivada del contorno CAD"},{"label":"Extensión local Y","value":0.3,"unit":"m","source":"433C/27BC, 433C/27BD, 433C/E6A3, 28D71","status":"derivada del contorno CAD"},{"label":"Cota inferior relativa adoptada","value":-1.2,"unit":"m","source":"6–6","status":"interpretación con conflicto conservado"},{"label":"Cota superior relativa adoptada","value":0.15,"unit":"m","source":"6–6","status":"documentada / separación por material"}],"geometry":[{"label":"Extensión de la malla en X","value":0.635269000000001,"unit":"m","source":"Geometría releída del IFC; datum absoluto de proceso provisional","status":"derivado"},{"label":"Extensión de la malla en Y","value":0.37892699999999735,"unit":"m","source":"Geometría releída del IFC; datum absoluto de proceso provisional","status":"derivado"},{"label":"Extensión de la malla en Z","value":1.35,"unit":"m","source":"Geometría releída del IFC; datum absoluto de proceso provisional","status":"derivado"},{"label":"Cota inferior de visualización","value":284.9,"unit":"m","source":"Geometría releída del IFC; datum absoluto de proceso provisional","status":"derivado"},{"label":"Cota superior de visualización","value":286.25,"unit":"m","source":"Geometría releída del IFC; datum absoluto de proceso provisional","status":"derivado"}]} | {"documentId":"LHD2609-JG00100-20260904","title":"Cimentaciones de equipos y pedestales del fabricante · revisión recibida 04/09/2026","date":"2026-09-04","sheet":"6–6","fileName":"LHD2609-JG00100_20260904.dwg","revisionCaveat":"Fecha de revisión tomada del nombre recibido; cajetines internos mantienen 02/07/2026 y algunos textos de plantilla.","sourceFileSha256":"b42eb027b7bc0b14c38d1d13514f4899b58a732aa8d0ba2ccf10fa2fc3192890"} | provisional | ["Planta: −2,200 m. Sección 6–6: fondo −2,000 m y coronación de losa −1,200 m. Se adopta sección; pendiente de aclaración."] | {"Cota inferior relativa (m)":-1.2,"Cota superior relativa (m)":0.15,"Cero absoluto de visualización (m)":286.1,"Estado del cero absoluto":"Provisional","Criterio":"Las cotas relativas proceden del dibujo; la equivalencia absoluta no está confirmada."} | {"boundingBoxM":{"min":[46.508971,47.391962,-0.1],"max":[47.14424,47.770889,1.25]},"extentsM":[0.635269,0.378927,1.35],"meshSurfaceM2":2.789999,"meshVolumeM3":0.243,"closedSolid":true,"basis":"Magnitudes de las mallas representadas, no cantidades certificadas de obra, compra o fabricación. Las partes pueden compartir superficies; no se suman como un despiece de materiales."} | {"profileId":"concrete_reinforced","name":"Hormigón armado · gris natural","materialName":"Hormigón armado · clase pendiente de confirmar","physicalMaterialStatus":"Clase no confirmada en la hoja de equipo","physicalMaterialSource":"Geometría de cimentación del fabricante; no se extrapola HA-30 de la nota de pedestales.","appearanceStatus":"criterio_visual","appearanceBasis":"Interpretación visual del material documental; el acabado, tono y parámetros PBR no son una especificación contractual.","note":"La apariencia gráfica no modifica ni confirma la especificación física del material."} | {"elementId":"found_0904_cff6b400f13210","ifcGuid":"0vdpCytWHI_vD7s7cGlXOx","ifcClass":"IfcFooting","buildingId":"process_plant","buildingName":"Zona de separación de aire","sourceDocumentId":"LHD2609-JG00100-20260904","sourceRepresentationKind":"foundation"} | {"layerId":"foundations","layerName":"Cimentaciones","role":"Cimentación industrial","basis":"Clasificación por función del elemento; no modifica las especificaciones documentales."} | {"profileId":"concrete_reinforced","name":"Hormigón armado · gris natural","status":"criterio_visual","basis":"Interpretación visual del material documental; el acabado, tono y parámetros PBR no son una especificación contractual.","physicalMaterialUnchanged":true} | 0.243 | Hormigón armado · clase pendiente de confirmar | Hormigón armado · gris natural | found_0904_cff6b400f13210 | Geometría de cimentación del fabricante; no se extrapola HA-30 de la nota de pedestales. | Clase no confirmada en la hoja de equipo | concrete_reinforced | [0.666667,0.662745,0.619608] | 0.96 | Zona de separación de aire; BIM · Cimentaciones | 0.635269 | 0.378927 | 1.35 | 284.9 | 286.25 | F-WE441-PLAN | ["WE441-PLAN"] | [] | 6–6 | ["433C/27BC","433C/27BD","433C/E6A3","28D71"] | F-WE441-PLAN/Cimentación del posenfriador WE441-PLAN · pedestal DZ6 2 | foundation | Geometría de fabricante; implantación absoluta provisional | WE441-PLAN | Cimentaciones de equipos y pedestales del fabricante · revisión recibida 04/09/2026 | 433C/27BC, 433C/27BD, 433C/E6A3, 28D71 | -1.2 | 0.15 | 0.18 | Cotas relativas del dibujo. La equivalencia con un datum absoluto está pendiente. | Z del modelo = cota relativa + 1,10 m. Correspondencia provisional con 286,10 m; no es cota de obra confirmada. | Sección y contornos del fabricante; incidencias conservadas | 0.6 | 0.3 | Planta: −2,200 m. Sección 6–6: fondo −2,000 m y coronación de losa −1,200 m. Se adopta sección; pendiente de aclaración.
Cimentación del posenfriador WE442-PLAN · cuerpo de hormigón | Parcela industrial Jinhong | Cimentación industrial | Cimentaciones de equipos y pedestales del fabricante · revisión recibida 04/09/2026 | 1.31757 | 2.51384 | 0.8 | 10.24 | 1.92 | process_plant | Zona de separación de aire | {"name":"Hormigón armado · clase pendiente de confirmar","status":"Clase no confirmada en la hoja de equipo","source":"Geometría de cimentación del fabricante; no se extrapola HA-30 de la nota de pedestales."} | {"documented":[{"label":"Extensión local X","value":1.0,"unit":"m","source":"27B6/27BC, 27B6/27BD, 27B6/E6A3, 28D71","status":"derivada del contorno CAD"},{"label":"Extensión local Y","value":2.4,"unit":"m","source":"27B6/27BC, 27B6/27BD, 27B6/E6A3, 28D71","status":"derivada del contorno CAD"},{"label":"Cota inferior relativa adoptada","value":-2,"unit":"m","source":"6–6","status":"interpretación con conflicto conservado"},{"label":"Cota superior relativa adoptada","value":-1.2,"unit":"m","source":"6–6","status":"documentada / separación por material"}],"geometry":[{"label":"Extensión de la malla en X","value":1.3175699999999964,"unit":"m","source":"Geometría releída del IFC; datum absoluto de proceso provisional","status":"derivado"},{"label":"Extensión de la malla en Y","value":2.513838,"unit":"m","source":"Geometría releída del IFC; datum absoluto de proceso provisional","status":"derivado"},{"label":"Extensión de la malla en Z","value":0.8,"unit":"m","source":"Geometría releída del IFC; datum absoluto de proceso provisional","status":"derivado"},{"label":"Cota inferior de visualización","value":284.1,"unit":"m","source":"Geometría releída del IFC; datum absoluto de proceso provisional","status":"derivado"},{"label":"Cota superior de visualización","value":284.9,"unit":"m","source":"Geometría releída del IFC; datum absoluto de proceso provisional","status":"derivado"}]} | {"documentId":"LHD2609-JG00100-20260904","title":"Cimentaciones de equipos y pedestales del fabricante · revisión recibida 04/09/2026","date":"2026-09-04","sheet":"6–6","fileName":"LHD2609-JG00100_20260904.dwg","revisionCaveat":"Fecha de revisión tomada del nombre recibido; cajetines internos mantienen 02/07/2026 y algunos textos de plantilla.","sourceFileSha256":"b42eb027b7bc0b14c38d1d13514f4899b58a732aa8d0ba2ccf10fa2fc3192890"} | provisional | ["Planta: −2,200 m. Sección 6–6: fondo −2,000 m y coronación de losa −1,200 m. Se adopta sección; pendiente de aclaración."] | {"Cota inferior relativa (m)":-2,"Cota superior relativa (m)":-1.2,"Cero absoluto de visualización (m)":286.1,"Estado del cero absoluto":"Provisional","Criterio":"Las cotas relativas proceden del dibujo; la equivalencia absoluta no está confirmada."} | {"boundingBoxM":{"min":[47.656927,46.876832,-0.9],"max":[48.974497,49.39067,-0.1]},"extentsM":[1.31757,2.513838,0.8],"meshSurfaceM2":10.239998,"meshVolumeM3":1.919999,"closedSolid":true,"basis":"Magnitudes de las mallas representadas, no cantidades certificadas de obra, compra o fabricación. Las partes pueden compartir superficies; no se suman como un despiece de materiales."} | {"profileId":"concrete_reinforced","name":"Hormigón armado · gris natural","materialName":"Hormigón armado · clase pendiente de confirmar","physicalMaterialStatus":"Clase no confirmada en la hoja de equipo","physicalMaterialSource":"Geometría de cimentación del fabricante; no se extrapola HA-30 de la nota de pedestales.","appearanceStatus":"criterio_visual","appearanceBasis":"Interpretación visual del material documental; el acabado, tono y parámetros PBR no son una especificación contractual.","note":"La apariencia gráfica no modifica ni confirma la especificación física del material."} | {"elementId":"found_0904_3cc1af80838d89","ifcGuid":"0Yqz6UHQfQvAmSFpBm1ofH","ifcClass":"IfcFooting","buildingId":"process_plant","buildingName":"Zona de separación de aire","sourceDocumentId":"LHD2609-JG00100-20260904","sourceRepresentationKind":"foundation"} | {"layerId":"foundations","layerName":"Cimentaciones","role":"Cimentación industrial","basis":"Clasificación por función del elemento; no modifica las especificaciones documentales."} | {"profileId":"concrete_reinforced","name":"Hormigón armado · gris natural","status":"criterio_visual","basis":"Interpretación visual del material documental; el acabado, tono y parámetros PBR no son una especificación contractual.","physicalMaterialUnchanged":true} | 1.92 | Hormigón armado · clase pendiente de confirmar | Hormigón armado · gris natural | found_0904_3cc1af80838d89 | Geometría de cimentación del fabricante; no se extrapola HA-30 de la nota de pedestales. | Clase no confirmada en la hoja de equipo | concrete_reinforced | [0.666667,0.662745,0.619608] | 0.96 | Zona de separación de aire; BIM · Cimentaciones | 1.31757 | 2.51384 | 0.8 | 284.1 | 284.9 | F-WE442-PLAN | ["WE442-PLAN"] | [] | 6–6 | ["27B6/27BC","27B6/27BD","27B6/E6A3","28D71"] | F-WE442-PLAN/Cimentación del posenfriador WE442-PLAN · cuerpo de hormigón | foundation | Geometría de fabricante; implantación absoluta provisional | WE442-PLAN | Cimentaciones de equipos y pedestales del fabricante · revisión recibida 04/09/2026 | 27B6/27BC, 27B6/27BD, 27B6/E6A3, 28D71 | -2 | -1.2 | 2.4 | Cotas relativas del dibujo. La equivalencia con un datum absoluto está pendiente. | Z del modelo = cota relativa + 1,10 m. Correspondencia provisional con 286,10 m; no es cota de obra confirmada. | Sección y contornos del fabricante; incidencias conservadas | 1 | 2.4 | Planta: −2,200 m. Sección 6–6: fondo −2,000 m y coronación de losa −1,200 m. Se adopta sección; pendiente de aclaración.
Cimentación del posenfriador WE442-PLAN · pedestal DZ6 1 | Parcela industrial Jinhong | Cimentación industrial | Cimentaciones de equipos y pedestales del fabricante · revisión recibida 04/09/2026 | 0.63527 | 0.378927 | 1.35 | 2.79 | 0.243 | process_plant | Zona de separación de aire | {"name":"Hormigón armado · clase pendiente de confirmar","status":"Clase no confirmada en la hoja de equipo","source":"Geometría de cimentación del fabricante; no se extrapola HA-30 de la nota de pedestales."} | {"documented":[{"label":"Extensión local X","value":0.6,"unit":"m","source":"27B6/27BC, 27B6/27BD, 27B6/E6A3, 28D71","status":"derivada del contorno CAD"},{"label":"Extensión local Y","value":0.3,"unit":"m","source":"27B6/27BC, 27B6/27BD, 27B6/E6A3, 28D71","status":"derivada del contorno CAD"},{"label":"Cota inferior relativa adoptada","value":-1.2,"unit":"m","source":"6–6","status":"interpretación con conflicto conservado"},{"label":"Cota superior relativa adoptada","value":0.15,"unit":"m","source":"6–6","status":"documentada / separación por material"}],"geometry":[{"label":"Extensión de la malla en X","value":0.6352699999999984,"unit":"m","source":"Geometría releída del IFC; datum absoluto de proceso provisional","status":"derivado"},{"label":"Extensión de la malla en Y","value":0.37892700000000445,"unit":"m","source":"Geometría releída del IFC; datum absoluto de proceso provisional","status":"derivado"},{"label":"Extensión de la malla en Z","value":1.35,"unit":"m","source":"Geometría releída del IFC; datum absoluto de proceso provisional","status":"derivado"},{"label":"Cota inferior de visualización","value":284.9,"unit":"m","source":"Geometría releída del IFC; datum absoluto de proceso provisional","status":"derivado"},{"label":"Cota superior de visualización","value":286.25,"unit":"m","source":"Geometría releída del IFC; datum absoluto de proceso provisional","status":"derivado"}]} | {"documentId":"LHD2609-JG00100-20260904","title":"Cimentaciones de equipos y pedestales del fabricante · revisión recibida 04/09/2026","date":"2026-09-04","sheet":"6–6","fileName":"LHD2609-JG00100_20260904.dwg","revisionCaveat":"Fecha de revisión tomada del nombre recibido; cajetines internos mantienen 02/07/2026 y algunos textos de plantilla.","sourceFileSha256":"b42eb027b7bc0b14c38d1d13514f4899b58a732aa8d0ba2ccf10fa2fc3192890"} | provisional | ["Planta: −2,200 m. Sección 6–6: fondo −2,000 m y coronación de losa −1,200 m. Se adopta sección; pendiente de aclaración."] | {"Cota inferior relativa (m)":-1.2,"Cota superior relativa (m)":0.15,"Cero absoluto de visualización (m)":286.1,"Estado del cero absoluto":"Provisional","Criterio":"Las cotas relativas proceden del dibujo; la equivalencia absoluta no está confirmada."} | {"boundingBoxM":{"min":[48.10023,48.687298,-0.1],"max":[48.7355,49.066225,1.25]},"extentsM":[0.63527,0.378927,1.35],"meshSurfaceM2":2.790001,"meshVolumeM3":0.243,"closedSolid":true,"basis":"Magnitudes de las mallas representadas, no cantidades certificadas de obra, compra o fabricación. Las partes pueden compartir superficies; no se suman como un despiece de materiales."} | {"profileId":"concrete_reinforced","name":"Hormigón armado · gris natural","materialName":"Hormigón armado · clase pendiente de confirmar","physicalMaterialStatus":"Clase no confirmada en la hoja de equipo","physicalMaterialSource":"Geometría de cimentación del fabricante; no se extrapola HA-30 de la nota de pedestales.","appearanceStatus":"criterio_visual","appearanceBasis":"Interpretación visual del material documental; el acabado, tono y parámetros PBR no son una especificación contractual.","note":"La apariencia gráfica no modifica ni confirma la especificación física del material."} | {"elementId":"found_0904_3470dba61bdc9f","ifcGuid":"2rnySLPYjQVPKjyWJTb5Pu","ifcClass":"IfcFooting","buildingId":"process_plant","buildingName":"Zona de separación de aire","sourceDocumentId":"LHD2609-JG00100-20260904","sourceRepresentationKind":"foundation"} | {"layerId":"foundations","layerName":"Cimentaciones","role":"Cimentación industrial","basis":"Clasificación por función del elemento; no modifica las especificaciones documentales."} | {"profileId":"concrete_reinforced","name":"Hormigón armado · gris natural","status":"criterio_visual","basis":"Interpretación visual del material documental; el acabado, tono y parámetros PBR no son una especificación contractual.","physicalMaterialUnchanged":true} | 0.243 | Hormigón armado · clase pendiente de confirmar | Hormigón armado · gris natural | found_0904_3470dba61bdc9f | Geometría de cimentación del fabricante; no se extrapola HA-30 de la nota de pedestales. | Clase no confirmada en la hoja de equipo | concrete_reinforced | [0.666667,0.662745,0.619608] | 0.96 | Zona de separación de aire; BIM · Cimentaciones | 0.63527 | 0.378927 | 1.35 | 284.9 | 286.25 | F-WE442-PLAN | ["WE442-PLAN"] | [] | 6–6 | ["27B6/27BC","27B6/27BD","27B6/E6A3","28D71"] | F-WE442-PLAN/Cimentación del posenfriador WE442-PLAN · pedestal DZ6 1 | foundation | Geometría de fabricante; implantación absoluta provisional | WE442-PLAN | Cimentaciones de equipos y pedestales del fabricante · revisión recibida 04/09/2026 | 27B6/27BC, 27B6/27BD, 27B6/E6A3, 28D71 | -1.2 | 0.15 | 0.18 | Cotas relativas del dibujo. La equivalencia con un datum absoluto está pendiente. | Z del modelo = cota relativa + 1,10 m. Correspondencia provisional con 286,10 m; no es cota de obra confirmada. | Sección y contornos del fabricante; incidencias conservadas | 0.6 | 0.3 | Planta: −2,200 m. Sección 6–6: fondo −2,000 m y coronación de losa −1,200 m. Se adopta sección; pendiente de aclaración.
Cimentación del posenfriador WE442-PLAN · pedestal DZ6 2 | Parcela industrial Jinhong | Cimentación industrial | Cimentaciones de equipos y pedestales del fabricante · revisión recibida 04/09/2026 | 0.63527 | 0.378926 | 1.35 | 2.79 | 0.243 | process_plant | Zona de separación de aire | {"name":"Hormigón armado · clase pendiente de confirmar","status":"Clase no confirmada en la hoja de equipo","source":"Geometría de cimentación del fabricante; no se extrapola HA-30 de la nota de pedestales."} | {"documented":[{"label":"Extensión local X","value":0.6,"unit":"m","source":"27B6/27BC, 27B6/27BD, 27B6/E6A3, 28D71","status":"derivada del contorno CAD"},{"label":"Extensión local Y","value":0.3,"unit":"m","source":"27B6/27BC, 27B6/27BD, 27B6/E6A3, 28D71","status":"derivada del contorno CAD"},{"label":"Cota inferior relativa adoptada","value":-1.2,"unit":"m","source":"6–6","status":"interpretación con conflicto conservado"},{"label":"Cota superior relativa adoptada","value":0.15,"unit":"m","source":"6–6","status":"documentada / separación por material"}],"geometry":[{"label":"Extensión de la malla en X","value":0.6352699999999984,"unit":"m","source":"Geometría releída del IFC; datum absoluto de proceso provisional","status":"derivado"},{"label":"Extensión de la malla en Y","value":0.3789259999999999,"unit":"m","source":"Geometría releída del IFC; datum absoluto de proceso provisional","status":"derivado"},{"label":"Extensión de la malla en Z","value":1.35,"unit":"m","source":"Geometría releída del IFC; datum absoluto de proceso provisional","status":"derivado"},{"label":"Cota inferior de visualización","value":284.9,"unit":"m","source":"Geometría releída del IFC; datum absoluto de proceso provisional","status":"derivado"},{"label":"Cota superior de visualización","value":286.25,"unit":"m","source":"Geometría releída del IFC; datum absoluto de proceso provisional","status":"derivado"}]} | {"documentId":"LHD2609-JG00100-20260904","title":"Cimentaciones de equipos y pedestales del fabricante · revisión recibida 04/09/2026","date":"2026-09-04","sheet":"6–6","fileName":"LHD2609-JG00100_20260904.dwg","revisionCaveat":"Fecha de revisión tomada del nombre recibido; cajetines internos mantienen 02/07/2026 y algunos textos de plantilla.","sourceFileSha256":"b42eb027b7bc0b14c38d1d13514f4899b58a732aa8d0ba2ccf10fa2fc3192890"} | provisional | ["Planta: −2,200 m. Sección 6–6: fondo −2,000 m y coronación de losa −1,200 m. Se adopta sección; pendiente de aclaración."] | {"Cota inferior relativa (m)":-1.2,"Cota superior relativa (m)":0.15,"Cero absoluto de visualización (m)":286.1,"Estado del cero absoluto":"Provisional","Criterio":"Las cotas relativas proceden del dibujo; la equivalencia absoluta no está confirmada."} | {"boundingBoxM":{"min":[47.895924,47.201277,-0.1],"max":[48.531194,47.580203,1.25]},"extentsM":[0.63527,0.378926,1.35],"meshSurfaceM2":2.789999,"meshVolumeM3":0.243,"closedSolid":true,"basis":"Magnitudes de las mallas representadas, no cantidades certificadas de obra, compra o fabricación. Las partes pueden compartir superficies; no se suman como un despiece de materiales."} | {"profileId":"concrete_reinforced","name":"Hormigón armado · gris natural","materialName":"Hormigón armado · clase pendiente de confirmar","physicalMaterialStatus":"Clase no confirmada en la hoja de equipo","physicalMaterialSource":"Geometría de cimentación del fabricante; no se extrapola HA-30 de la nota de pedestales.","appearanceStatus":"criterio_visual","appearanceBasis":"Interpretación visual del material documental; el acabado, tono y parámetros PBR no son una especificación contractual.","note":"La apariencia gráfica no modifica ni confirma la especificación física del material."} | {"elementId":"found_0904_7f59eb478aceab","ifcGuid":"0P43RfUdHTzR9IQrPR6led","ifcClass":"IfcFooting","buildingId":"process_plant","buildingName":"Zona de separación de aire","sourceDocumentId":"LHD2609-JG00100-20260904","sourceRepresentationKind":"foundation"} | {"layerId":"foundations","layerName":"Cimentaciones","role":"Cimentación industrial","basis":"Clasificación por función del elemento; no modifica las especificaciones documentales."} | {"profileId":"concrete_reinforced","name":"Hormigón armado · gris natural","status":"criterio_visual","basis":"Interpretación visual del material documental; el acabado, tono y parámetros PBR no son una especificación contractual.","physicalMaterialUnchanged":true} | 0.243 | Hormigón armado · clase pendiente de confirmar | Hormigón armado · gris natural | found_0904_7f59eb478aceab | Geometría de cimentación del fabricante; no se extrapola HA-30 de la nota de pedestales. | Clase no confirmada en la hoja de equipo | concrete_reinforced | [0.666667,0.662745,0.619608] | 0.96 | Zona de separación de aire; BIM · Cimentaciones | 0.63527 | 0.378926 | 1.35 | 284.9 | 286.25 | F-WE442-PLAN | ["WE442-PLAN"] | [] | 6–6 | ["27B6/27BC","27B6/27BD","27B6/E6A3","28D71"] | F-WE442-PLAN/Cimentación del posenfriador WE442-PLAN · pedestal DZ6 2 | foundation | Geometría de fabricante; implantación absoluta provisional | WE442-PLAN | Cimentaciones de equipos y pedestales del fabricante · revisión recibida 04/09/2026 | 27B6/27BC, 27B6/27BD, 27B6/E6A3, 28D71 | -1.2 | 0.15 | 0.18 | Cotas relativas del dibujo. La equivalencia con un datum absoluto está pendiente. | Z del modelo = cota relativa + 1,10 m. Correspondencia provisional con 286,10 m; no es cota de obra confirmada. | Sección y contornos del fabricante; incidencias conservadas | 0.6 | 0.3 | Planta: −2,200 m. Sección 6–6: fondo −2,000 m y coronación de losa −1,200 m. Se adopta sección; pendiente de aclaración.
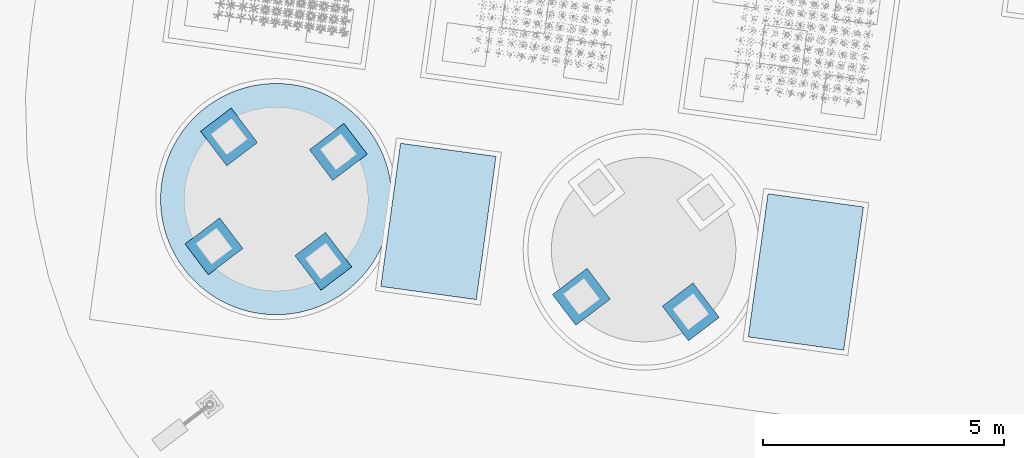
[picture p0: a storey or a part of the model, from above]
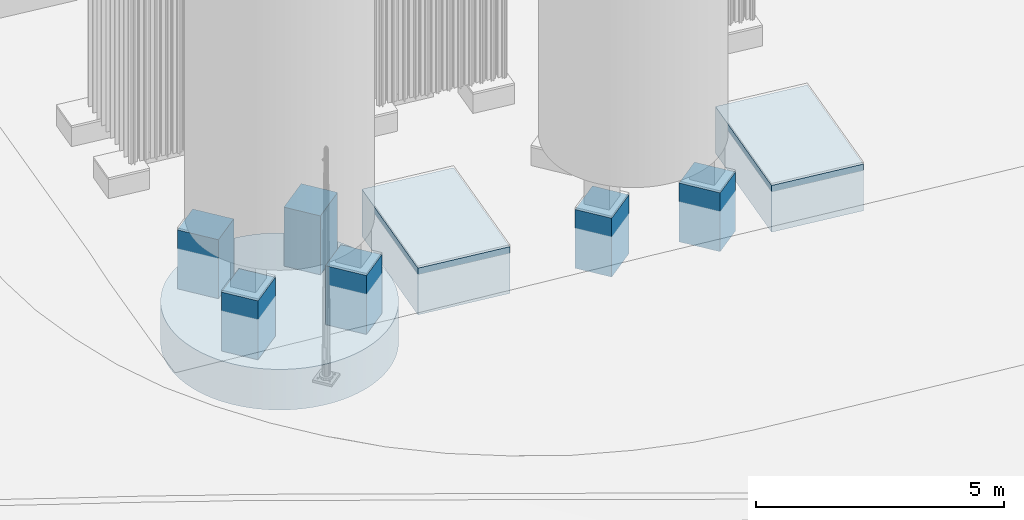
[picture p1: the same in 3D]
Properties of the parts of a building model (IFC4), part 67 of 134

# IfcFooting (214)
Name | In | Description = category = Categoria = Funcion | Document | ExtensionX (m) | ExtensionY (m) | ExtensionZ (m) | SuperficieDeLaMalla (m2) | VolumenGeometrico (m3) | buildingId | buildingName | material | dimensions | JH_InformacionBIM, source = DocumentoFuente | JH_InformacionBIM, status = EstadoDeInformacion | issues = IncidenciasPendientes | positioning = PosicionYEstado | geometryMetrics | materialAppearance | visualizationIdentity | classification | appearance | Volumen geométrico (m³) | JH_Trazabilidad, Material = name | Acabado de visualización = Acabado | Identificador | JH_EvidenciaDeMaterial, source | JH_EvidenciaDeMaterial, status | Perfil | ColorRGB | Rugosidad | Group | Extensión de la malla en X (m) | Extensión de la malla en Y (m) | Extensión de la malla en Z (m) = Espesor o altura real de sección (m) | Cota inferior de visualización (m) | Cota superior de visualización (m) | assemblyId = Conjunto de cimentación | equipmentIds | supportPositionIds | sectionRef = Sección de referencia | sourceCadHandles | stableElementKey | representationKind | geometryStatus | Equipos asociados | Documento de origen | Identificadores CAD de referencia | Cota inferior relativa (m) = Cota inferior relativa adoptada (m) | Cota superior relativa (m) = Cota superior relativa adoptada (m) | Área de planta (m²) | Referencia vertical | Implantación para visualización | Estado de la geometría | Extensión local X (m) | Extensión local Y (m) | Incidencias de origen
Cimentación del depósito SV1801A · cuerpo de hormigón | Parcela industrial Jinhong | Cimentación industrial | Cimentaciones de equipos y pedestales del fabricante · revisión recibida 04/09/2026 | 4.79992 | 4.79992 | 1 | 51.2637 | 18.0923 | process_plant | Zona de separación de aire | {"name":"Hormigón armado · clase pendiente de confirmar","status":"Clase no confirmada en la hoja de equipo","source":"Geometría de cimentación del fabricante; no se extrapola HA-30 de la nota de pedestales."} | {"documented":[{"label":"Extensión local X","value":4.8,"unit":"m","source":"254C/2589, 254C/2554, 1FEB7","status":"derivada del contorno CAD"},{"label":"Extensión local Y","value":4.8,"unit":"m","source":"254C/2589, 254C/2554, 1FEB7","status":"derivada del contorno CAD"},{"label":"Cota inferior relativa adoptada","value":-2,"unit":"m","source":"7–7","status":"interpretación con conflicto conservado"},{"label":"Cota superior relativa adoptada","value":-1,"unit":"m","source":"7–7","status":"documentada / separación por material"}],"geometry":[{"label":"Extensión de la malla en X","value":4.799921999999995,"unit":"m","source":"Geometría releída del IFC; datum absoluto de proceso provisional","status":"derivado"},{"label":"Extensión de la malla en Y","value":4.799921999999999,"unit":"m","source":"Geometría releída del IFC; datum absoluto de proceso provisional","status":"derivado"},{"label":"Extensión de la malla en Z","value":1.0,"unit":"m","source":"Geometría releída del IFC; datum absoluto de proceso provisional","status":"derivado"},{"label":"Cota inferior de visualización","value":284.1,"unit":"m","source":"Geometría releída del IFC; datum absoluto de proceso provisional","status":"derivado"},{"label":"Cota superior de visualización","value":285.1,"unit":"m","source":"Geometría releída del IFC; datum absoluto de proceso provisional","status":"derivado"}]} | {"documentId":"LHD2609-JG00100-20260904","title":"Cimentaciones de equipos y pedestales del fabricante · revisión recibida 04/09/2026","date":"2026-09-04","sheet":"7–7","fileName":"LHD2609-JG00100_20260904.dwg","revisionCaveat":"Fecha de revisión tomada del nombre recibido; cajetines internos mantienen 02/07/2026 y algunos textos de plantilla.","sourceFileSha256":"b42eb027b7bc0b14c38d1d13514f4899b58a732aa8d0ba2ccf10fa2fc3192890"} | provisional | ["La planta contiene una cota de losa distinta de la sección. Sección 7–7 adoptada: fondo −2,000 m, coronación de losa −1,000 m; apoyos acabados +0,500 m."] | {"Cota inferior relativa (m)":-2,"Cota superior relativa (m)":-1,"Cero absoluto de visualización (m)":286.1,"Estado del cero absoluto":"Provisional","Criterio":"Las cotas relativas proceden del dibujo; la equivalencia absoluta no está confirmada."} | {"boundingBoxM":{"min":[33.977023,30.114059,-0.9],"max":[38.776945,34.913981,0.1]},"extentsM":[4.799922,4.799922,1.0],"meshSurfaceM2":51.26366,"meshVolumeM3":18.092344,"closedSolid":true,"basis":"Magnitudes de las mallas representadas, no cantidades certificadas de obra, compra o fabricación. Las partes pueden compartir superficies; no se suman como un despiece de materiales."} | {"profileId":"concrete_reinforced","name":"Hormigón armado · gris natural","materialName":"Hormigón armado · clase pendiente de confirmar","physicalMaterialStatus":"Clase no confirmada en la hoja de equipo","physicalMaterialSource":"Geometría de cimentación del fabricante; no se extrapola HA-30 de la nota de pedestales.","appearanceStatus":"criterio_visual","appearanceBasis":"Interpretación visual del material documental; el acabado, tono y parámetros PBR no son una especificación contractual.","note":"La apariencia gráfica no modifica ni confirma la especificación física del material."} | {"elementId":"found_0904_cbe5e32142275f","ifcGuid":"0sfiHZON9HCvEbsCDThbEe","ifcClass":"IfcFooting","buildingId":"process_plant","buildingName":"Zona de separación de aire","sourceDocumentId":"LHD2609-JG00100-20260904","sourceRepresentationKind":"foundation"} | {"layerId":"foundations","layerName":"Cimentaciones","role":"Cimentación industrial","basis":"Clasificación por función del elemento; no modifica las especificaciones documentales."} | {"profileId":"concrete_reinforced","name":"Hormigón armado · gris natural","status":"criterio_visual","basis":"Interpretación visual del material documental; el acabado, tono y parámetros PBR no son una especificación contractual.","physicalMaterialUnchanged":true} | 18.0923 | Hormigón armado · clase pendiente de confirmar | Hormigón armado · gris natural | found_0904_cbe5e32142275f | Geometría de cimentación del fabricante; no se extrapola HA-30 de la nota de pedestales. | Clase no confirmada en la hoja de equipo | concrete_reinforced | [0.666667,0.662745,0.619608] | 0.96 | Zona de separación de aire; BIM · Cimentaciones | 4.79992 | 4.79992 | 1 | 284.1 | 285.1 | F-SV1801A | ["SV1801A"] | [] | 7–7 | ["254C/2589","254C/2554","1FEB7"] | F-SV1801A/Cimentación del depósito SV1801A · cuerpo de hormigón | foundation | Geometría de fabricante; implantación absoluta provisional | SV1801A | Cimentaciones de equipos y pedestales del fabricante · revisión recibida 04/09/2026 | 254C/2589, 254C/2554, 1FEB7 | -2 | -1 | 18.0923 | Cotas relativas del dibujo. La equivalencia con un datum absoluto está pendiente. | Z del modelo = cota relativa + 1,10 m. Correspondencia provisional con 286,10 m; no es cota de obra confirmada. | Sección y contornos del fabricante; incidencias conservadas | 4.8 | 4.8 | La planta contiene una cota de losa distinta de la sección. Sección 7–7 adoptada: fondo −2,000 m, coronación de losa −1,000 m; apoyos acabados +0,500 m.
Cimentación del depósito SV1801A · pedestal DZ7 1 | Parcela industrial Jinhong | Cimentación industrial | Cimentaciones de equipos y pedestales del fabricante · revisión recibida 04/09/2026 | 1.20051 | 1.18125 | 1.45 | 6.37 | 1.044 | process_plant | Zona de separación de aire | {"name":"Hormigón armado · clase pendiente de confirmar","status":"Clase no confirmada en la hoja de equipo","source":"Geometría de cimentación del fabricante; no se extrapola HA-30 de la nota de pedestales."} | {"documented":[{"label":"Extensión local X","value":1.202082,"unit":"m","source":"254C/2589, 254C/2554, 1FEB7","status":"derivada del contorno CAD"},{"label":"Extensión local Y","value":1.202082,"unit":"m","source":"254C/2589, 254C/2554, 1FEB7","status":"derivada del contorno CAD"},{"label":"Cota inferior relativa adoptada","value":-1,"unit":"m","source":"7–7","status":"interpretación con conflicto conservado"},{"label":"Cota superior relativa adoptada","value":0.45,"unit":"m","source":"7–7","status":"documentada / separación por material"}],"geometry":[{"label":"Extensión de la malla en X","value":1.2005099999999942,"unit":"m","source":"Geometría releída del IFC; datum absoluto de proceso provisional","status":"derivado"},{"label":"Extensión de la malla en Y","value":1.181249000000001,"unit":"m","source":"Geometría releída del IFC; datum absoluto de proceso provisional","status":"derivado"},{"label":"Extensión de la malla en Z","value":1.45,"unit":"m","source":"Geometría releída del IFC; datum absoluto de proceso provisional","status":"derivado"},{"label":"Cota inferior de visualización","value":285.1,"unit":"m","source":"Geometría releída del IFC; datum absoluto de proceso provisional","status":"derivado"},{"label":"Cota superior de visualización","value":286.55,"unit":"m","source":"Geometría releída del IFC; datum absoluto de proceso provisional","status":"derivado"}]} | {"documentId":"LHD2609-JG00100-20260904","title":"Cimentaciones de equipos y pedestales del fabricante · revisión recibida 04/09/2026","date":"2026-09-04","sheet":"7–7","fileName":"LHD2609-JG00100_20260904.dwg","revisionCaveat":"Fecha de revisión tomada del nombre recibido; cajetines internos mantienen 02/07/2026 y algunos textos de plantilla.","sourceFileSha256":"b42eb027b7bc0b14c38d1d13514f4899b58a732aa8d0ba2ccf10fa2fc3192890"} | provisional | ["La planta contiene una cota de losa distinta de la sección. Sección 7–7 adoptada: fondo −2,000 m, coronación de losa −1,000 m; apoyos acabados +0,500 m."] | {"Cota inferior relativa (m)":-1,"Cota superior relativa (m)":0.45,"Cero absoluto de visualización (m)":286.1,"Estado del cero absoluto":"Provisional","Criterio":"Las cotas relativas proceden del dibujo; la equivalencia absoluta no está confirmada."} | {"boundingBoxM":{"min":[37.06759,32.90221,0.1],"max":[38.2681,34.083459,1.55]},"extentsM":[1.20051,1.181249,1.45],"meshSurfaceM2":6.370003,"meshVolumeM3":1.044001,"closedSolid":true,"basis":"Magnitudes de las mallas representadas, no cantidades certificadas de obra, compra o fabricación. Las partes pueden compartir superficies; no se suman como un despiece de materiales."} | {"profileId":"concrete_reinforced","name":"Hormigón armado · gris natural","materialName":"Hormigón armado · clase pendiente de confirmar","physicalMaterialStatus":"Clase no confirmada en la hoja de equipo","physicalMaterialSource":"Geometría de cimentación del fabricante; no se extrapola HA-30 de la nota de pedestales.","appearanceStatus":"criterio_visual","appearanceBasis":"Interpretación visual del material documental; el acabado, tono y parámetros PBR no son una especificación contractual.","note":"La apariencia gráfica no modifica ni confirma la especificación física del material."} | {"elementId":"found_0904_0858fe779cb4ca","ifcGuid":"0tdQ$WbsPLpfpDIFYprLEw","ifcClass":"IfcFooting","buildingId":"process_plant","buildingName":"Zona de separación de aire","sourceDocumentId":"LHD2609-JG00100-20260904","sourceRepresentationKind":"foundation"} | {"layerId":"foundations","layerName":"Cimentaciones","role":"Cimentación industrial","basis":"Clasificación por función del elemento; no modifica las especificaciones documentales."} | {"profileId":"concrete_reinforced","name":"Hormigón armado · gris natural","status":"criterio_visual","basis":"Interpretación visual del material documental; el acabado, tono y parámetros PBR no son una especificación contractual.","physicalMaterialUnchanged":true} | 1.044 | Hormigón armado · clase pendiente de confirmar | Hormigón armado · gris natural | found_0904_0858fe779cb4ca | Geometría de cimentación del fabricante; no se extrapola HA-30 de la nota de pedestales. | Clase no confirmada en la hoja de equipo | concrete_reinforced | [0.666667,0.662745,0.619608] | 0.96 | Zona de separación de aire; BIM · Cimentaciones | 1.20051 | 1.18125 | 1.45 | 285.1 | 286.55 | F-SV1801A | ["SV1801A"] | [] | 7–7 | ["254C/2589","254C/2554","1FEB7"] | F-SV1801A/Cimentación del depósito SV1801A · pedestal DZ7 1 | foundation | Geometría de fabricante; implantación absoluta provisional | SV1801A | Cimentaciones de equipos y pedestales del fabricante · revisión recibida 04/09/2026 | 254C/2589, 254C/2554, 1FEB7 | -1 | 0.45 | 0.72 | Cotas relativas del dibujo. La equivalencia con un datum absoluto está pendiente. | Z del modelo = cota relativa + 1,10 m. Correspondencia provisional con 286,10 m; no es cota de obra confirmada. | Sección y contornos del fabricante; incidencias conservadas | 1.20208 | 1.20208 | La planta contiene una cota de losa distinta de la sección. Sección 7–7 adoptada: fondo −2,000 m, coronación de losa −1,000 m; apoyos acabados +0,500 m.
Cimentación del depósito SV1801A · pedestal DZ7 2 | Parcela industrial Jinhong | Cimentación industrial | Cimentaciones de equipos y pedestales del fabricante · revisión recibida 04/09/2026 | 1.18125 | 1.20051 | 1.45 | 6.37001 | 1.044 | process_plant | Zona de separación de aire | {"name":"Hormigón armado · clase pendiente de confirmar","status":"Clase no confirmada en la hoja de equipo","source":"Geometría de cimentación del fabricante; no se extrapola HA-30 de la nota de pedestales."} | {"documented":[{"label":"Extensión local X","value":1.202082,"unit":"m","source":"254C/2589, 254C/2554, 1FEB7","status":"derivada del contorno CAD"},{"label":"Extensión local Y","value":1.202082,"unit":"m","source":"254C/2589, 254C/2554, 1FEB7","status":"derivada del contorno CAD"},{"label":"Cota inferior relativa adoptada","value":-1,"unit":"m","source":"7–7","status":"interpretación con conflicto conservado"},{"label":"Cota superior relativa adoptada","value":0.45,"unit":"m","source":"7–7","status":"documentada / separación por material"}],"geometry":[{"label":"Extensión de la malla en X","value":1.181249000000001,"unit":"m","source":"Geometría releída del IFC; datum absoluto de proceso provisional","status":"derivado"},{"label":"Extensión de la malla en Y","value":1.2005110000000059,"unit":"m","source":"Geometría releída del IFC; datum absoluto de proceso provisional","status":"derivado"},{"label":"Extensión de la malla en Z","value":1.45,"unit":"m","source":"Geometría releída del IFC; datum absoluto de proceso provisional","status":"derivado"},{"label":"Cota inferior de visualización","value":285.1,"unit":"m","source":"Geometría releída del IFC; datum absoluto de proceso provisional","status":"derivado"},{"label":"Cota superior de visualización","value":286.55,"unit":"m","source":"Geometría releída del IFC; datum absoluto de proceso provisional","status":"derivado"}]} | {"documentId":"LHD2609-JG00100-20260904","title":"Cimentaciones de equipos y pedestales del fabricante · revisión recibida 04/09/2026","date":"2026-09-04","sheet":"7–7","fileName":"LHD2609-JG00100_20260904.dwg","revisionCaveat":"Fecha de revisión tomada del nombre recibido; cajetines internos mantienen 02/07/2026 y algunos textos de plantilla.","sourceFileSha256":"b42eb027b7bc0b14c38d1d13514f4899b58a732aa8d0ba2ccf10fa2fc3192890"} | provisional | ["La planta contiene una cota de losa distinta de la sección. Sección 7–7 adoptada: fondo −2,000 m, coronación de losa −1,000 m; apoyos acabados +0,500 m."] | {"Cota inferior relativa (m)":-1,"Cota superior relativa (m)":0.45,"Cero absoluto de visualización (m)":286.1,"Estado del cero absoluto":"Provisional","Criterio":"Las cotas relativas proceden del dibujo; la equivalencia absoluta no está confirmada."} | {"boundingBoxM":{"min":[34.807545,33.204626,0.1],"max":[35.988794,34.405137,1.55]},"extentsM":[1.181249,1.200511,1.45],"meshSurfaceM2":6.370006,"meshVolumeM3":1.044002,"closedSolid":true,"basis":"Magnitudes de las mallas representadas, no cantidades certificadas de obra, compra o fabricación. Las partes pueden compartir superficies; no se suman como un despiece de materiales."} | {"profileId":"concrete_reinforced","name":"Hormigón armado · gris natural","materialName":"Hormigón armado · clase pendiente de confirmar","physicalMaterialStatus":"Clase no confirmada en la hoja de equipo","physicalMaterialSource":"Geometría de cimentación del fabricante; no se extrapola HA-30 de la nota de pedestales.","appearanceStatus":"criterio_visual","appearanceBasis":"Interpretación visual del material documental; el acabado, tono y parámetros PBR no son una especificación contractual.","note":"La apariencia gráfica no modifica ni confirma la especificación física del material."} | {"elementId":"found_0904_8347a0e234c768","ifcGuid":"1QNXdbCfvSw9nBKzCc6_wy","ifcClass":"IfcFooting","buildingId":"process_plant","buildingName":"Zona de separación de aire","sourceDocumentId":"LHD2609-JG00100-20260904","sourceRepresentationKind":"foundation"} | {"layerId":"foundations","layerName":"Cimentaciones","role":"Cimentación industrial","basis":"Clasificación por función del elemento; no modifica las especificaciones documentales."} | {"profileId":"concrete_reinforced","name":"Hormigón armado · gris natural","status":"criterio_visual","basis":"Interpretación visual del material documental; el acabado, tono y parámetros PBR no son una especificación contractual.","physicalMaterialUnchanged":true} | 1.044 | Hormigón armado · clase pendiente de confirmar | Hormigón armado · gris natural | found_0904_8347a0e234c768 | Geometría de cimentación del fabricante; no se extrapola HA-30 de la nota de pedestales. | Clase no confirmada en la hoja de equipo | concrete_reinforced | [0.666667,0.662745,0.619608] | 0.96 | Zona de separación de aire; BIM · Cimentaciones | 1.18125 | 1.20051 | 1.45 | 285.1 | 286.55 | F-SV1801A | ["SV1801A"] | [] | 7–7 | ["254C/2589","254C/2554","1FEB7"] | F-SV1801A/Cimentación del depósito SV1801A · pedestal DZ7 2 | foundation | Geometría de fabricante; implantación absoluta provisional | SV1801A | Cimentaciones de equipos y pedestales del fabricante · revisión recibida 04/09/2026 | 254C/2589, 254C/2554, 1FEB7 | -1 | 0.45 | 0.72 | Cotas relativas del dibujo. La equivalencia con un datum absoluto está pendiente. | Z del modelo = cota relativa + 1,10 m. Correspondencia provisional con 286,10 m; no es cota de obra confirmada. | Sección y contornos del fabricante; incidencias conservadas | 1.20208 | 1.20208 | La planta contiene una cota de losa distinta de la sección. Sección 7–7 adoptada: fondo −2,000 m, coronación de losa −1,000 m; apoyos acabados +0,500 m.
Cimentación del depósito SV1801A · pedestal DZ7 3 | Parcela industrial Jinhong | Cimentación industrial | Cimentaciones de equipos y pedestales del fabricante · revisión recibida 04/09/2026 | 1.18125 | 1.20051 | 1.45 | 6.37 | 1.044 | process_plant | Zona de separación de aire | {"name":"Hormigón armado · clase pendiente de confirmar","status":"Clase no confirmada en la hoja de equipo","source":"Geometría de cimentación del fabricante; no se extrapola HA-30 de la nota de pedestales."} | {"documented":[{"label":"Extensión local X","value":1.202082,"unit":"m","source":"254C/2589, 254C/2554, 1FEB7","status":"derivada del contorno CAD"},{"label":"Extensión local Y","value":1.202082,"unit":"m","source":"254C/2589, 254C/2554, 1FEB7","status":"derivada del contorno CAD"},{"label":"Cota inferior relativa adoptada","value":-1,"unit":"m","source":"7–7","status":"interpretación con conflicto conservado"},{"label":"Cota superior relativa adoptada","value":0.45,"unit":"m","source":"7–7","status":"documentada / separación por material"}],"geometry":[{"label":"Extensión de la malla en X","value":1.181249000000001,"unit":"m","source":"Geometría releída del IFC; datum absoluto de proceso provisional","status":"derivado"},{"label":"Extensión de la malla en Y","value":1.2005100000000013,"unit":"m","source":"Geometría releída del IFC; datum absoluto de proceso provisional","status":"derivado"},{"label":"Extensión de la malla en Z","value":1.45,"unit":"m","source":"Geometría releída del IFC; datum absoluto de proceso provisional","status":"derivado"},{"label":"Cota inferior de visualización","value":285.1,"unit":"m","source":"Geometría releída del IFC; datum absoluto de proceso provisional","status":"derivado"},{"label":"Cota superior de visualización","value":286.55,"unit":"m","source":"Geometría releída del IFC; datum absoluto de proceso provisional","status":"derivado"}]} | {"documentId":"LHD2609-JG00100-20260904","title":"Cimentaciones de equipos y pedestales del fabricante · revisión recibida 04/09/2026","date":"2026-09-04","sheet":"7–7","fileName":"LHD2609-JG00100_20260904.dwg","revisionCaveat":"Fecha de revisión tomada del nombre recibido; cajetines internos mantienen 02/07/2026 y algunos textos de plantilla.","sourceFileSha256":"b42eb027b7bc0b14c38d1d13514f4899b58a732aa8d0ba2ccf10fa2fc3192890"} | provisional | ["La planta contiene una cota de losa distinta de la sección. Sección 7–7 adoptada: fondo −2,000 m, coronación de losa −1,000 m; apoyos acabados +0,500 m."] | {"Cota inferior relativa (m)":-1,"Cota superior relativa (m)":0.45,"Cero absoluto de visualización (m)":286.1,"Estado del cero absoluto":"Provisional","Criterio":"Las cotas relativas proceden del dibujo; la equivalencia absoluta no está confirmada."} | {"boundingBoxM":{"min":[36.765174,30.622904,0.1],"max":[37.946423,31.823414,1.55]},"extentsM":[1.181249,1.20051,1.45],"meshSurfaceM2":6.370003,"meshVolumeM3":1.044001,"closedSolid":true,"basis":"Magnitudes de las mallas representadas, no cantidades certificadas de obra, compra o fabricación. Las partes pueden compartir superficies; no se suman como un despiece de materiales."} | {"profileId":"concrete_reinforced","name":"Hormigón armado · gris natural","materialName":"Hormigón armado · clase pendiente de confirmar","physicalMaterialStatus":"Clase no confirmada en la hoja de equipo","physicalMaterialSource":"Geometría de cimentación del fabricante; no se extrapola HA-30 de la nota de pedestales.","appearanceStatus":"criterio_visual","appearanceBasis":"Interpretación visual del material documental; el acabado, tono y parámetros PBR no son una especificación contractual.","note":"La apariencia gráfica no modifica ni confirma la especificación física del material."} | {"elementId":"found_0904_81ea899e189605","ifcGuid":"0A1QlYPkLJJwBlcsOmclRh","ifcClass":"IfcFooting","buildingId":"process_plant","buildingName":"Zona de separación de aire","sourceDocumentId":"LHD2609-JG00100-20260904","sourceRepresentationKind":"foundation"} | {"layerId":"foundations","layerName":"Cimentaciones","role":"Cimentación industrial","basis":"Clasificación por función del elemento; no modifica las especificaciones documentales."} | {"profileId":"concrete_reinforced","name":"Hormigón armado · gris natural","status":"criterio_visual","basis":"Interpretación visual del material documental; el acabado, tono y parámetros PBR no son una especificación contractual.","physicalMaterialUnchanged":true} | 1.044 | Hormigón armado · clase pendiente de confirmar | Hormigón armado · gris natural | found_0904_81ea899e189605 | Geometría de cimentación del fabricante; no se extrapola HA-30 de la nota de pedestales. | Clase no confirmada en la hoja de equipo | concrete_reinforced | [0.666667,0.662745,0.619608] | 0.96 | Zona de separación de aire; BIM · Cimentaciones | 1.18125 | 1.20051 | 1.45 | 285.1 | 286.55 | F-SV1801A | ["SV1801A"] | [] | 7–7 | ["254C/2589","254C/2554","1FEB7"] | F-SV1801A/Cimentación del depósito SV1801A · pedestal DZ7 3 | foundation | Geometría de fabricante; implantación absoluta provisional | SV1801A | Cimentaciones de equipos y pedestales del fabricante · revisión recibida 04/09/2026 | 254C/2589, 254C/2554, 1FEB7 | -1 | 0.45 | 0.72 | Cotas relativas del dibujo. La equivalencia con un datum absoluto está pendiente. | Z del modelo = cota relativa + 1,10 m. Correspondencia provisional con 286,10 m; no es cota de obra confirmada. | Sección y contornos del fabricante; incidencias conservadas | 1.20208 | 1.20208 | La planta contiene una cota de losa distinta de la sección. Sección 7–7 adoptada: fondo −2,000 m, coronación de losa −1,000 m; apoyos acabados +0,500 m.
Cimentación del depósito SV1801A · pedestal DZ7 4 | Parcela industrial Jinhong | Cimentación industrial | Cimentaciones de equipos y pedestales del fabricante · revisión recibida 04/09/2026 | 1.20051 | 1.18125 | 1.45 | 6.37 | 1.044 | process_plant | Zona de separación de aire | {"name":"Hormigón armado · clase pendiente de confirmar","status":"Clase no confirmada en la hoja de equipo","source":"Geometría de cimentación del fabricante; no se extrapola HA-30 de la nota de pedestales."} | {"documented":[{"label":"Extensión local X","value":1.202082,"unit":"m","source":"254C/2589, 254C/2554, 1FEB7","status":"derivada del contorno CAD"},{"label":"Extensión local Y","value":1.202082,"unit":"m","source":"254C/2589, 254C/2554, 1FEB7","status":"derivada del contorno CAD"},{"label":"Cota inferior relativa adoptada","value":-1,"unit":"m","source":"7–7","status":"interpretación con conflicto conservado"},{"label":"Cota superior relativa adoptada","value":0.45,"unit":"m","source":"7–7","status":"documentada / separación por material"}],"geometry":[{"label":"Extensión de la malla en X","value":1.2005099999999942,"unit":"m","source":"Geometría releída del IFC; datum absoluto de proceso provisional","status":"derivado"},{"label":"Extensión de la malla en Y","value":1.181248,"unit":"m","source":"Geometría releída del IFC; datum absoluto de proceso provisional","status":"derivado"},{"label":"Extensión de la malla en Z","value":1.45,"unit":"m","source":"Geometría releída del IFC; datum absoluto de proceso provisional","status":"derivado"},{"label":"Cota inferior de visualización","value":285.1,"unit":"m","source":"Geometría releída del IFC; datum absoluto de proceso provisional","status":"derivado"},{"label":"Cota superior de visualización","value":286.55,"unit":"m","source":"Geometría releída del IFC; datum absoluto de proceso provisional","status":"derivado"}]} | {"documentId":"LHD2609-JG00100-20260904","title":"Cimentaciones de equipos y pedestales del fabricante · revisión recibida 04/09/2026","date":"2026-09-04","sheet":"7–7","fileName":"LHD2609-JG00100_20260904.dwg","revisionCaveat":"Fecha de revisión tomada del nombre recibido; cajetines internos mantienen 02/07/2026 y algunos textos de plantilla.","sourceFileSha256":"b42eb027b7bc0b14c38d1d13514f4899b58a732aa8d0ba2ccf10fa2fc3192890"} | provisional | ["La planta contiene una cota de losa distinta de la sección. Sección 7–7 adoptada: fondo −2,000 m, coronación de losa −1,000 m; apoyos acabados +0,500 m."] | {"Cota inferior relativa (m)":-1,"Cota superior relativa (m)":0.45,"Cero absoluto de visualización (m)":286.1,"Estado del cero absoluto":"Provisional","Criterio":"Las cotas relativas proceden del dibujo; la equivalencia absoluta no está confirmada."} | {"boundingBoxM":{"min":[34.485868,30.944582,0.1],"max":[35.686378,32.12583,1.55]},"extentsM":[1.20051,1.181248,1.45],"meshSurfaceM2":6.37,"meshVolumeM3":1.044,"closedSolid":true,"basis":"Magnitudes de las mallas representadas, no cantidades certificadas de obra, compra o fabricación. Las partes pueden compartir superficies; no se suman como un despiece de materiales."} | {"profileId":"concrete_reinforced","name":"Hormigón armado · gris natural","materialName":"Hormigón armado · clase pendiente de confirmar","physicalMaterialStatus":"Clase no confirmada en la hoja de equipo","physicalMaterialSource":"Geometría de cimentación del fabricante; no se extrapola HA-30 de la nota de pedestales.","appearanceStatus":"criterio_visual","appearanceBasis":"Interpretación visual del material documental; el acabado, tono y parámetros PBR no son una especificación contractual.","note":"La apariencia gráfica no modifica ni confirma la especificación física del material."} | {"elementId":"found_0904_4f2b61caf5b971","ifcGuid":"1EsF9z7N5JZeYt39zJSPUG","ifcClass":"IfcFooting","buildingId":"process_plant","buildingName":"Zona de separación de aire","sourceDocumentId":"LHD2609-JG00100-20260904","sourceRepresentationKind":"foundation"} | {"layerId":"foundations","layerName":"Cimentaciones","role":"Cimentación industrial","basis":"Clasificación por función del elemento; no modifica las especificaciones documentales."} | {"profileId":"concrete_reinforced","name":"Hormigón armado · gris natural","status":"criterio_visual","basis":"Interpretación visual del material documental; el acabado, tono y parámetros PBR no son una especificación contractual.","physicalMaterialUnchanged":true} | 1.044 | Hormigón armado · clase pendiente de confirmar | Hormigón armado · gris natural | found_0904_4f2b61caf5b971 | Geometría de cimentación del fabricante; no se extrapola HA-30 de la nota de pedestales. | Clase no confirmada en la hoja de equipo | concrete_reinforced | [0.666667,0.662745,0.619608] | 0.96 | Zona de separación de aire; BIM · Cimentaciones | 1.20051 | 1.18125 | 1.45 | 285.1 | 286.55 | F-SV1801A | ["SV1801A"] | [] | 7–7 | ["254C/2589","254C/2554","1FEB7"] | F-SV1801A/Cimentación del depósito SV1801A · pedestal DZ7 4 | foundation | Geometría de fabricante; implantación absoluta provisional | SV1801A | Cimentaciones de equipos y pedestales del fabricante · revisión recibida 04/09/2026 | 254C/2589, 254C/2554, 1FEB7 | -1 | 0.45 | 0.72 | Cotas relativas del dibujo. La equivalencia con un datum absoluto está pendiente. | Z del modelo = cota relativa + 1,10 m. Correspondencia provisional con 286,10 m; no es cota de obra confirmada. | Sección y contornos del fabricante; incidencias conservadas | 1.20208 | 1.20208 | La planta contiene una cota de losa distinta de la sección. Sección 7–7 adoptada: fondo −2,000 m, coronación de losa −1,000 m; apoyos acabados +0,500 m.
Cimentación del depósito SV1801B · cuerpo de hormigón | Parcela industrial Jinhong | Cimentación industrial | Cimentaciones de equipos y pedestales del fabricante · revisión recibida 04/09/2026 | 4.79992 | 4.79992 | 1 | 51.2637 | 18.0923 | process_plant | Zona de separación de aire | {"name":"Hormigón armado · clase pendiente de confirmar","status":"Clase no confirmada en la hoja de equipo","source":"Geometría de cimentación del fabricante; no se extrapola HA-30 de la nota de pedestales."} | {"documented":[{"label":"Extensión local X","value":4.8,"unit":"m","source":"26E2/2589, 26E2/2554, 1FEB7","status":"derivada del contorno CAD"},{"label":"Extensión local Y","value":4.8,"unit":"m","source":"26E2/2589, 26E2/2554, 1FEB7","status":"derivada del contorno CAD"},{"label":"Cota inferior relativa adoptada","value":-2,"unit":"m","source":"7–7","status":"interpretación con conflicto conservado"},{"label":"Cota superior relativa adoptada","value":-1,"unit":"m","source":"7–7","status":"documentada / separación por material"}],"geometry":[{"label":"Extensión de la malla en X","value":4.799921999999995,"unit":"m","source":"Geometría releída del IFC; datum absoluto de proceso provisional","status":"derivado"},{"label":"Extensión de la malla en Y","value":4.799922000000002,"unit":"m","source":"Geometría releída del IFC; datum absoluto de proceso provisional","status":"derivado"},{"label":"Extensión de la malla en Z","value":1.0,"unit":"m","source":"Geometría releída del IFC; datum absoluto de proceso provisional","status":"derivado"},{"label":"Cota inferior de visualización","value":284.1,"unit":"m","source":"Geometría releída del IFC; datum absoluto de proceso provisional","status":"derivado"},{"label":"Cota superior de visualización","value":285.1,"unit":"m","source":"Geometría releída del IFC; datum absoluto de proceso provisional","status":"derivado"}]} | {"documentId":"LHD2609-JG00100-20260904","title":"Cimentaciones de equipos y pedestales del fabricante · revisión recibida 04/09/2026","date":"2026-09-04","sheet":"7–7","fileName":"LHD2609-JG00100_20260904.dwg","revisionCaveat":"Fecha de revisión tomada del nombre recibido; cajetines internos mantienen 02/07/2026 y algunos textos de plantilla.","sourceFileSha256":"b42eb027b7bc0b14c38d1d13514f4899b58a732aa8d0ba2ccf10fa2fc3192890"} | provisional | ["La planta contiene una cota de losa distinta de la sección. Sección 7–7 adoptada: fondo −2,000 m, coronación de losa −1,000 m; apoyos acabados +0,500 m."] | {"Cota inferior relativa (m)":-2,"Cota superior relativa (m)":-1,"Cero absoluto de visualización (m)":286.1,"Estado del cero absoluto":"Provisional","Criterio":"Las cotas relativas proceden del dibujo; la equivalencia absoluta no está confirmada."} | {"boundingBoxM":{"min":[41.605265,29.065289,-0.9],"max":[46.405187,33.865211,0.1]},"extentsM":[4.799922,4.799922,1.0],"meshSurfaceM2":51.26366,"meshVolumeM3":18.092344,"closedSolid":true,"basis":"Magnitudes de las mallas representadas, no cantidades certificadas de obra, compra o fabricación. Las partes pueden compartir superficies; no se suman como un despiece de materiales."} | {"profileId":"concrete_reinforced","name":"Hormigón armado · gris natural","materialName":"Hormigón armado · clase pendiente de confirmar","physicalMaterialStatus":"Clase no confirmada en la hoja de equipo","physicalMaterialSource":"Geometría de cimentación del fabricante; no se extrapola HA-30 de la nota de pedestales.","appearanceStatus":"criterio_visual","appearanceBasis":"Interpretación visual del material documental; el acabado, tono y parámetros PBR no son una especificación contractual.","note":"La apariencia gráfica no modifica ni confirma la especificación física del material."} | {"elementId":"found_0904_2674dba16f3e98","ifcGuid":"3gLePEyG5S8uo72SMFIEDX","ifcClass":"IfcFooting","buildingId":"process_plant","buildingName":"Zona de separación de aire","sourceDocumentId":"LHD2609-JG00100-20260904","sourceRepresentationKind":"foundation"} | {"layerId":"foundations","layerName":"Cimentaciones","role":"Cimentación industrial","basis":"Clasificación por función del elemento; no modifica las especificaciones documentales."} | {"profileId":"concrete_reinforced","name":"Hormigón armado · gris natural","status":"criterio_visual","basis":"Interpretación visual del material documental; el acabado, tono y parámetros PBR no son una especificación contractual.","physicalMaterialUnchanged":true} | 18.0923 | Hormigón armado · clase pendiente de confirmar | Hormigón armado · gris natural | found_0904_2674dba16f3e98 | Geometría de cimentación del fabricante; no se extrapola HA-30 de la nota de pedestales. | Clase no confirmada en la hoja de equipo | concrete_reinforced | [0.666667,0.662745,0.619608] | 0.96 | Zona de separación de aire; BIM · Cimentaciones | 4.79992 | 4.79992 | 1 | 284.1 | 285.1 | F-SV1801B | ["SV1801B"] | [] | 7–7 | ["26E2/2589","26E2/2554","1FEB7"] | F-SV1801B/Cimentación del depósito SV1801B · cuerpo de hormigón | foundation | Geometría de fabricante; implantación absoluta provisional | SV1801B | Cimentaciones de equipos y pedestales del fabricante · revisión recibida 04/09/2026 | 26E2/2589, 26E2/2554, 1FEB7 | -2 | -1 | 18.0923 | Cotas relativas del dibujo. La equivalencia con un datum absoluto está pendiente. | Z del modelo = cota relativa + 1,10 m. Correspondencia provisional con 286,10 m; no es cota de obra confirmada. | Sección y contornos del fabricante; incidencias conservadas | 4.8 | 4.8 | La planta contiene una cota de losa distinta de la sección. Sección 7–7 adoptada: fondo −2,000 m, coronación de losa −1,000 m; apoyos acabados +0,500 m.
Cimentación del depósito SV1801B · pedestal DZ7 1 | Parcela industrial Jinhong | Cimentación industrial | Cimentaciones de equipos y pedestales del fabricante · revisión recibida 04/09/2026 | 1.20051 | 1.18125 | 1.45 | 6.37001 | 1.044 | process_plant | Zona de separación de aire | {"name":"Hormigón armado · clase pendiente de confirmar","status":"Clase no confirmada en la hoja de equipo","source":"Geometría de cimentación del fabricante; no se extrapola HA-30 de la nota de pedestales."} | {"documented":[{"label":"Extensión local X","value":1.202082,"unit":"m","source":"26E2/2589, 26E2/2554, 1FEB7","status":"derivada del contorno CAD"},{"label":"Extensión local Y","value":1.202082,"unit":"m","source":"26E2/2589, 26E2/2554, 1FEB7","status":"derivada del contorno CAD"},{"label":"Cota inferior relativa adoptada","value":-1,"unit":"m","source":"7–7","status":"interpretación con conflicto conservado"},{"label":"Cota superior relativa adoptada","value":0.45,"unit":"m","source":"7–7","status":"documentada / separación por material"}],"geometry":[{"label":"Extensión de la malla en X","value":1.2005109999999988,"unit":"m","source":"Geometría releída del IFC; datum absoluto de proceso provisional","status":"derivado"},{"label":"Extensión de la malla en Y","value":1.181249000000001,"unit":"m","source":"Geometría releída del IFC; datum absoluto de proceso provisional","status":"derivado"},{"label":"Extensión de la malla en Z","value":1.45,"unit":"m","source":"Geometría releída del IFC; datum absoluto de proceso provisional","status":"derivado"},{"label":"Cota inferior de visualización","value":285.1,"unit":"m","source":"Geometría releída del IFC; datum absoluto de proceso provisional","status":"derivado"},{"label":"Cota superior de visualización","value":286.55,"unit":"m","source":"Geometría releída del IFC; datum absoluto de proceso provisional","status":"derivado"}]} | {"documentId":"LHD2609-JG00100-20260904","title":"Cimentaciones de equipos y pedestales del fabricante · revisión recibida 04/09/2026","date":"2026-09-04","sheet":"7–7","fileName":"LHD2609-JG00100_20260904.dwg","revisionCaveat":"Fecha de revisión tomada del nombre recibido; cajetines internos mantienen 02/07/2026 y algunos textos de plantilla.","sourceFileSha256":"b42eb027b7bc0b14c38d1d13514f4899b58a732aa8d0ba2ccf10fa2fc3192890"} | provisional | ["La planta contiene una cota de losa distinta de la sección. Sección 7–7 adoptada: fondo −2,000 m, coronación de losa −1,000 m; apoyos acabados +0,500 m."] | {"Cota inferior relativa (m)":-1,"Cota superior relativa (m)":0.45,"Cero absoluto de visualización (m)":286.1,"Estado del cero absoluto":"Provisional","Criterio":"Las cotas relativas proceden del dibujo; la equivalencia absoluta no está confirmada."} | {"boundingBoxM":{"min":[44.695832,31.85344,0.1],"max":[45.896343,33.034689,1.55]},"extentsM":[1.200511,1.181249,1.45],"meshSurfaceM2":6.370006,"meshVolumeM3":1.044002,"closedSolid":true,"basis":"Magnitudes de las mallas representadas, no cantidades certificadas de obra, compra o fabricación. Las partes pueden compartir superficies; no se suman como un despiece de materiales."} | {"profileId":"concrete_reinforced","name":"Hormigón armado · gris natural","materialName":"Hormigón armado · clase pendiente de confirmar","physicalMaterialStatus":"Clase no confirmada en la hoja de equipo","physicalMaterialSource":"Geometría de cimentación del fabricante; no se extrapola HA-30 de la nota de pedestales.","appearanceStatus":"criterio_visual","appearanceBasis":"Interpretación visual del material documental; el acabado, tono y parámetros PBR no son una especificación contractual.","note":"La apariencia gráfica no modifica ni confirma la especificación física del material."} | {"elementId":"found_0904_73bf36418cda5f","ifcGuid":"1MXWbL9rDNlgr1pMO9KAA8","ifcClass":"IfcFooting","buildingId":"process_plant","buildingName":"Zona de separación de aire","sourceDocumentId":"LHD2609-JG00100-20260904","sourceRepresentationKind":"foundation"} | {"layerId":"foundations","layerName":"Cimentaciones","role":"Cimentación industrial","basis":"Clasificación por función del elemento; no modifica las especificaciones documentales."} | {"profileId":"concrete_reinforced","name":"Hormigón armado · gris natural","status":"criterio_visual","basis":"Interpretación visual del material documental; el acabado, tono y parámetros PBR no son una especificación contractual.","physicalMaterialUnchanged":true} | 1.044 | Hormigón armado · clase pendiente de confirmar | Hormigón armado · gris natural | found_0904_73bf36418cda5f | Geometría de cimentación del fabricante; no se extrapola HA-30 de la nota de pedestales. | Clase no confirmada en la hoja de equipo | concrete_reinforced | [0.666667,0.662745,0.619608] | 0.96 | Zona de separación de aire; BIM · Cimentaciones | 1.20051 | 1.18125 | 1.45 | 285.1 | 286.55 | F-SV1801B | ["SV1801B"] | [] | 7–7 | ["26E2/2589","26E2/2554","1FEB7"] | F-SV1801B/Cimentación del depósito SV1801B · pedestal DZ7 1 | foundation | Geometría de fabricante; implantación absoluta provisional | SV1801B | Cimentaciones de equipos y pedestales del fabricante · revisión recibida 04/09/2026 | 26E2/2589, 26E2/2554, 1FEB7 | -1 | 0.45 | 0.72 | Cotas relativas del dibujo. La equivalencia con un datum absoluto está pendiente. | Z del modelo = cota relativa + 1,10 m. Correspondencia provisional con 286,10 m; no es cota de obra confirmada. | Sección y contornos del fabricante; incidencias conservadas | 1.20208 | 1.20208 | La planta contiene una cota de losa distinta de la sección. Sección 7–7 adoptada: fondo −2,000 m, coronación de losa −1,000 m; apoyos acabados +0,500 m.
Cimentación del depósito SV1801B · pedestal DZ7 2 | Parcela industrial Jinhong | Cimentación industrial | Cimentaciones de equipos y pedestales del fabricante · revisión recibida 04/09/2026 | 1.18125 | 1.20051 | 1.45 | 6.37 | 1.044 | process_plant | Zona de separación de aire | {"name":"Hormigón armado · clase pendiente de confirmar","status":"Clase no confirmada en la hoja de equipo","source":"Geometría de cimentación del fabricante; no se extrapola HA-30 de la nota de pedestales."} | {"documented":[{"label":"Extensión local X","value":1.202082,"unit":"m","source":"26E2/2589, 26E2/2554, 1FEB7","status":"derivada del contorno CAD"},{"label":"Extensión local Y","value":1.202082,"unit":"m","source":"26E2/2589, 26E2/2554, 1FEB7","status":"derivada del contorno CAD"},{"label":"Cota inferior relativa adoptada","value":-1,"unit":"m","source":"7–7","status":"interpretación con conflicto conservado"},{"label":"Cota superior relativa adoptada","value":0.45,"unit":"m","source":"7–7","status":"documentada / separación por material"}],"geometry":[{"label":"Extensión de la malla en X","value":1.1812479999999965,"unit":"m","source":"Geometría releída del IFC; datum absoluto de proceso provisional","status":"derivado"},{"label":"Extensión de la malla en Y","value":1.2005100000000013,"unit":"m","source":"Geometría releída del IFC; datum absoluto de proceso provisional","status":"derivado"},{"label":"Extensión de la malla en Z","value":1.45,"unit":"m","source":"Geometría releída del IFC; datum absoluto de proceso provisional","status":"derivado"},{"label":"Cota inferior de visualización","value":285.1,"unit":"m","source":"Geometría releída del IFC; datum absoluto de proceso provisional","status":"derivado"},{"label":"Cota superior de visualización","value":286.55,"unit":"m","source":"Geometría releída del IFC; datum absoluto de proceso provisional","status":"derivado"}]} | {"documentId":"LHD2609-JG00100-20260904","title":"Cimentaciones de equipos y pedestales del fabricante · revisión recibida 04/09/2026","date":"2026-09-04","sheet":"7–7","fileName":"LHD2609-JG00100_20260904.dwg","revisionCaveat":"Fecha de revisión tomada del nombre recibido; cajetines internos mantienen 02/07/2026 y algunos textos de plantilla.","sourceFileSha256":"b42eb027b7bc0b14c38d1d13514f4899b58a732aa8d0ba2ccf10fa2fc3192890"} | provisional | ["La planta contiene una cota de losa distinta de la sección. Sección 7–7 adoptada: fondo −2,000 m, coronación de losa −1,000 m; apoyos acabados +0,500 m."] | {"Cota inferior relativa (m)":-1,"Cota superior relativa (m)":0.45,"Cero absoluto de visualización (m)":286.1,"Estado del cero absoluto":"Provisional","Criterio":"Las cotas relativas proceden del dibujo; la equivalencia absoluta no está confirmada."} | {"boundingBoxM":{"min":[42.435788,32.155856,0.1],"max":[43.617036,33.356366,1.55]},"extentsM":[1.181248,1.20051,1.45],"meshSurfaceM2":6.37,"meshVolumeM3":1.044,"closedSolid":true,"basis":"Magnitudes de las mallas representadas, no cantidades certificadas de obra, compra o fabricación. Las partes pueden compartir superficies; no se suman como un despiece de materiales."} | {"profileId":"concrete_reinforced","name":"Hormigón armado · gris natural","materialName":"Hormigón armado · clase pendiente de confirmar","physicalMaterialStatus":"Clase no confirmada en la hoja de equipo","physicalMaterialSource":"Geometría de cimentación del fabricante; no se extrapola HA-30 de la nota de pedestales.","appearanceStatus":"criterio_visual","appearanceBasis":"Interpretación visual del material documental; el acabado, tono y parámetros PBR no son una especificación contractual.","note":"La apariencia gráfica no modifica ni confirma la especificación física del material."} | {"elementId":"found_0904_6d4f95d05f13d2","ifcGuid":"1SwsYAFzrGEOnMGbYzuDfw","ifcClass":"IfcFooting","buildingId":"process_plant","buildingName":"Zona de separación de aire","sourceDocumentId":"LHD2609-JG00100-20260904","sourceRepresentationKind":"foundation"} | {"layerId":"foundations","layerName":"Cimentaciones","role":"Cimentación industrial","basis":"Clasificación por función del elemento; no modifica las especificaciones documentales."} | {"profileId":"concrete_reinforced","name":"Hormigón armado · gris natural","status":"criterio_visual","basis":"Interpretación visual del material documental; el acabado, tono y parámetros PBR no son una especificación contractual.","physicalMaterialUnchanged":true} | 1.044 | Hormigón armado · clase pendiente de confirmar | Hormigón armado · gris natural | found_0904_6d4f95d05f13d2 | Geometría de cimentación del fabricante; no se extrapola HA-30 de la nota de pedestales. | Clase no confirmada en la hoja de equipo | concrete_reinforced | [0.666667,0.662745,0.619608] | 0.96 | Zona de separación de aire; BIM · Cimentaciones | 1.18125 | 1.20051 | 1.45 | 285.1 | 286.55 | F-SV1801B | ["SV1801B"] | [] | 7–7 | ["26E2/2589","26E2/2554","1FEB7"] | F-SV1801B/Cimentación del depósito SV1801B · pedestal DZ7 2 | foundation | Geometría de fabricante; implantación absoluta provisional | SV1801B | Cimentaciones de equipos y pedestales del fabricante · revisión recibida 04/09/2026 | 26E2/2589, 26E2/2554, 1FEB7 | -1 | 0.45 | 0.72 | Cotas relativas del dibujo. La equivalencia con un datum absoluto está pendiente. | Z del modelo = cota relativa + 1,10 m. Correspondencia provisional con 286,10 m; no es cota de obra confirmada. | Sección y contornos del fabricante; incidencias conservadas | 1.20208 | 1.20208 | La planta contiene una cota de losa distinta de la sección. Sección 7–7 adoptada: fondo −2,000 m, coronación de losa −1,000 m; apoyos acabados +0,500 m.
Cimentación del depósito SV1801B · pedestal DZ7 3 | Parcela industrial Jinhong | Cimentación industrial | Cimentaciones de equipos y pedestales del fabricante · revisión recibida 04/09/2026 | 1.18125 | 1.20051 | 1.45 | 6.37 | 1.044 | process_plant | Zona de separación de aire | {"name":"Hormigón armado · clase pendiente de confirmar","status":"Clase no confirmada en la hoja de equipo","source":"Geometría de cimentación del fabricante; no se extrapola HA-30 de la nota de pedestales."} | {"documented":[{"label":"Extensión local X","value":1.202082,"unit":"m","source":"26E2/2589, 26E2/2554, 1FEB7","status":"derivada del contorno CAD"},{"label":"Extensión local Y","value":1.202082,"unit":"m","source":"26E2/2589, 26E2/2554, 1FEB7","status":"derivada del contorno CAD"},{"label":"Cota inferior relativa adoptada","value":-1,"unit":"m","source":"7–7","status":"interpretación con conflicto conservado"},{"label":"Cota superior relativa adoptada","value":0.45,"unit":"m","source":"7–7","status":"documentada / separación por material"}],"geometry":[{"label":"Extensión de la malla en X","value":1.181249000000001,"unit":"m","source":"Geometría releída del IFC; datum absoluto de proceso provisional","status":"derivado"},{"label":"Extensión de la malla en Y","value":1.2005099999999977,"unit":"m","source":"Geometría releída del IFC; datum absoluto de proceso provisional","status":"derivado"},{"label":"Extensión de la malla en Z","value":1.45,"unit":"m","source":"Geometría releída del IFC; datum absoluto de proceso provisional","status":"derivado"},{"label":"Cota inferior de visualización","value":285.1,"unit":"m","source":"Geometría releída del IFC; datum absoluto de proceso provisional","status":"derivado"},{"label":"Cota superior de visualización","value":286.55,"unit":"m","source":"Geometría releída del IFC; datum absoluto de proceso provisional","status":"derivado"}]} | {"documentId":"LHD2609-JG00100-20260904","title":"Cimentaciones de equipos y pedestales del fabricante · revisión recibida 04/09/2026","date":"2026-09-04","sheet":"7–7","fileName":"LHD2609-JG00100_20260904.dwg","revisionCaveat":"Fecha de revisión tomada del nombre recibido; cajetines internos mantienen 02/07/2026 y algunos textos de plantilla.","sourceFileSha256":"b42eb027b7bc0b14c38d1d13514f4899b58a732aa8d0ba2ccf10fa2fc3192890"} | provisional | ["La planta contiene una cota de losa distinta de la sección. Sección 7–7 adoptada: fondo −2,000 m, coronación de losa −1,000 m; apoyos acabados +0,500 m."] | {"Cota inferior relativa (m)":-1,"Cota superior relativa (m)":0.45,"Cero absoluto de visualización (m)":286.1,"Estado del cero absoluto":"Provisional","Criterio":"Las cotas relativas proceden del dibujo; la equivalencia absoluta no está confirmada."} | {"boundingBoxM":{"min":[44.393416,29.574134,0.1],"max":[45.574665,30.774644,1.55]},"extentsM":[1.181249,1.20051,1.45],"meshSurfaceM2":6.370003,"meshVolumeM3":1.044001,"closedSolid":true,"basis":"Magnitudes de las mallas representadas, no cantidades certificadas de obra, compra o fabricación. Las partes pueden compartir superficies; no se suman como un despiece de materiales."} | {"profileId":"concrete_reinforced","name":"Hormigón armado · gris natural","materialName":"Hormigón armado · clase pendiente de confirmar","physicalMaterialStatus":"Clase no confirmada en la hoja de equipo","physicalMaterialSource":"Geometría de cimentación del fabricante; no se extrapola HA-30 de la nota de pedestales.","appearanceStatus":"criterio_visual","appearanceBasis":"Interpretación visual del material documental; el acabado, tono y parámetros PBR no son una especificación contractual.","note":"La apariencia gráfica no modifica ni confirma la especificación física del material."} | {"elementId":"found_0904_2f52643828a88e","ifcGuid":"2PrufOOv1RlRW1zThQvUPo","ifcClass":"IfcFooting","buildingId":"process_plant","buildingName":"Zona de separación de aire","sourceDocumentId":"LHD2609-JG00100-20260904","sourceRepresentationKind":"foundation"} | {"layerId":"foundations","layerName":"Cimentaciones","role":"Cimentación industrial","basis":"Clasificación por función del elemento; no modifica las especificaciones documentales."} | {"profileId":"concrete_reinforced","name":"Hormigón armado · gris natural","status":"criterio_visual","basis":"Interpretación visual del material documental; el acabado, tono y parámetros PBR no son una especificación contractual.","physicalMaterialUnchanged":true} | 1.044 | Hormigón armado · clase pendiente de confirmar | Hormigón armado · gris natural | found_0904_2f52643828a88e | Geometría de cimentación del fabricante; no se extrapola HA-30 de la nota de pedestales. | Clase no confirmada en la hoja de equipo | concrete_reinforced | [0.666667,0.662745,0.619608] | 0.96 | Zona de separación de aire; BIM · Cimentaciones | 1.18125 | 1.20051 | 1.45 | 285.1 | 286.55 | F-SV1801B | ["SV1801B"] | [] | 7–7 | ["26E2/2589","26E2/2554","1FEB7"] | F-SV1801B/Cimentación del depósito SV1801B · pedestal DZ7 3 | foundation | Geometría de fabricante; implantación absoluta provisional | SV1801B | Cimentaciones de equipos y pedestales del fabricante · revisión recibida 04/09/2026 | 26E2/2589, 26E2/2554, 1FEB7 | -1 | 0.45 | 0.72 | Cotas relativas del dibujo. La equivalencia con un datum absoluto está pendiente. | Z del modelo = cota relativa + 1,10 m. Correspondencia provisional con 286,10 m; no es cota de obra confirmada. | Sección y contornos del fabricante; incidencias conservadas | 1.20208 | 1.20208 | La planta contiene una cota de losa distinta de la sección. Sección 7–7 adoptada: fondo −2,000 m, coronación de losa −1,000 m; apoyos acabados +0,500 m.
Cimentación del depósito SV1801B · pedestal DZ7 4 | Parcela industrial Jinhong | Cimentación industrial | Cimentaciones de equipos y pedestales del fabricante · revisión recibida 04/09/2026 | 1.20051 | 1.18125 | 1.45 | 6.37001 | 1.044 | process_plant | Zona de separación de aire | {"name":"Hormigón armado · clase pendiente de confirmar","status":"Clase no confirmada en la hoja de equipo","source":"Geometría de cimentación del fabricante; no se extrapola HA-30 de la nota de pedestales."} | {"documented":[{"label":"Extensión local X","value":1.202082,"unit":"m","source":"26E2/2589, 26E2/2554, 1FEB7","status":"derivada del contorno CAD"},{"label":"Extensión local Y","value":1.202082,"unit":"m","source":"26E2/2589, 26E2/2554, 1FEB7","status":"derivada del contorno CAD"},{"label":"Cota inferior relativa adoptada","value":-1,"unit":"m","source":"7–7","status":"interpretación con conflicto conservado"},{"label":"Cota superior relativa adoptada","value":0.45,"unit":"m","source":"7–7","status":"documentada / separación por material"}],"geometry":[{"label":"Extensión de la malla en X","value":1.2005110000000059,"unit":"m","source":"Geometría releída del IFC; datum absoluto de proceso provisional","status":"derivado"},{"label":"Extensión de la malla en Y","value":1.181249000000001,"unit":"m","source":"Geometría releída del IFC; datum absoluto de proceso provisional","status":"derivado"},{"label":"Extensión de la malla en Z","value":1.45,"unit":"m","source":"Geometría releída del IFC; datum absoluto de proceso provisional","status":"derivado"},{"label":"Cota inferior de visualización","value":285.1,"unit":"m","source":"Geometría releída del IFC; datum absoluto de proceso provisional","status":"derivado"},{"label":"Cota superior de visualización","value":286.55,"unit":"m","source":"Geometría releída del IFC; datum absoluto de proceso provisional","status":"derivado"}]} | {"documentId":"LHD2609-JG00100-20260904","title":"Cimentaciones de equipos y pedestales del fabricante · revisión recibida 04/09/2026","date":"2026-09-04","sheet":"7–7","fileName":"LHD2609-JG00100_20260904.dwg","revisionCaveat":"Fecha de revisión tomada del nombre recibido; cajetines internos mantienen 02/07/2026 y algunos textos de plantilla.","sourceFileSha256":"b42eb027b7bc0b14c38d1d13514f4899b58a732aa8d0ba2ccf10fa2fc3192890"} | provisional | ["La planta contiene una cota de losa distinta de la sección. Sección 7–7 adoptada: fondo −2,000 m, coronación de losa −1,000 m; apoyos acabados +0,500 m."] | {"Cota inferior relativa (m)":-1,"Cota superior relativa (m)":0.45,"Cero absoluto de visualización (m)":286.1,"Estado del cero absoluto":"Provisional","Criterio":"Las cotas relativas proceden del dibujo; la equivalencia absoluta no está confirmada."} | {"boundingBoxM":{"min":[42.11411,29.895811,0.1],"max":[43.314621,31.07706,1.55]},"extentsM":[1.200511,1.181249,1.45],"meshSurfaceM2":6.370006,"meshVolumeM3":1.044002,"closedSolid":true,"basis":"Magnitudes de las mallas representadas, no cantidades certificadas de obra, compra o fabricación. Las partes pueden compartir superficies; no se suman como un despiece de materiales."} | {"profileId":"concrete_reinforced","name":"Hormigón armado · gris natural","materialName":"Hormigón armado · clase pendiente de confirmar","physicalMaterialStatus":"Clase no confirmada en la hoja de equipo","physicalMaterialSource":"Geometría de cimentación del fabricante; no se extrapola HA-30 de la nota de pedestales.","appearanceStatus":"criterio_visual","appearanceBasis":"Interpretación visual del material documental; el acabado, tono y parámetros PBR no son una especificación contractual.","note":"La apariencia gráfica no modifica ni confirma la especificación física del material."} | {"elementId":"found_0904_45f2f263423089","ifcGuid":"0SKu62HpvRZv9Hl7x1MPSK","ifcClass":"IfcFooting","buildingId":"process_plant","buildingName":"Zona de separación de aire","sourceDocumentId":"LHD2609-JG00100-20260904","sourceRepresentationKind":"foundation"} | {"layerId":"foundations","layerName":"Cimentaciones","role":"Cimentación industrial","basis":"Clasificación por función del elemento; no modifica las especificaciones documentales."} | {"profileId":"concrete_reinforced","name":"Hormigón armado · gris natural","status":"criterio_visual","basis":"Interpretación visual del material documental; el acabado, tono y parámetros PBR no son una especificación contractual.","physicalMaterialUnchanged":true} | 1.044 | Hormigón armado · clase pendiente de confirmar | Hormigón armado · gris natural | found_0904_45f2f263423089 | Geometría de cimentación del fabricante; no se extrapola HA-30 de la nota de pedestales. | Clase no confirmada en la hoja de equipo | concrete_reinforced | [0.666667,0.662745,0.619608] | 0.96 | Zona de separación de aire; BIM · Cimentaciones | 1.20051 | 1.18125 | 1.45 | 285.1 | 286.55 | F-SV1801B | ["SV1801B"] | [] | 7–7 | ["26E2/2589","26E2/2554","1FEB7"] | F-SV1801B/Cimentación del depósito SV1801B · pedestal DZ7 4 | foundation | Geometría de fabricante; implantación absoluta provisional | SV1801B | Cimentaciones de equipos y pedestales del fabricante · revisión recibida 04/09/2026 | 26E2/2589, 26E2/2554, 1FEB7 | -1 | 0.45 | 0.72 | Cotas relativas del dibujo. La equivalencia con un datum absoluto está pendiente. | Z del modelo = cota relativa + 1,10 m. Correspondencia provisional con 286,10 m; no es cota de obra confirmada. | Sección y contornos del fabricante; incidencias conservadas | 1.20208 | 1.20208 | La planta contiene una cota de losa distinta de la sección. Sección 7–7 adoptada: fondo −2,000 m, coronación de losa −1,000 m; apoyos acabados +0,500 m.
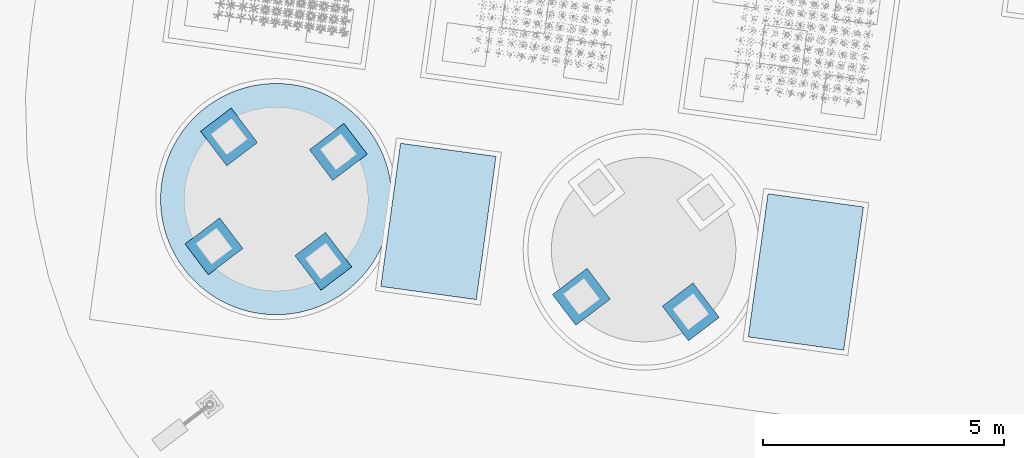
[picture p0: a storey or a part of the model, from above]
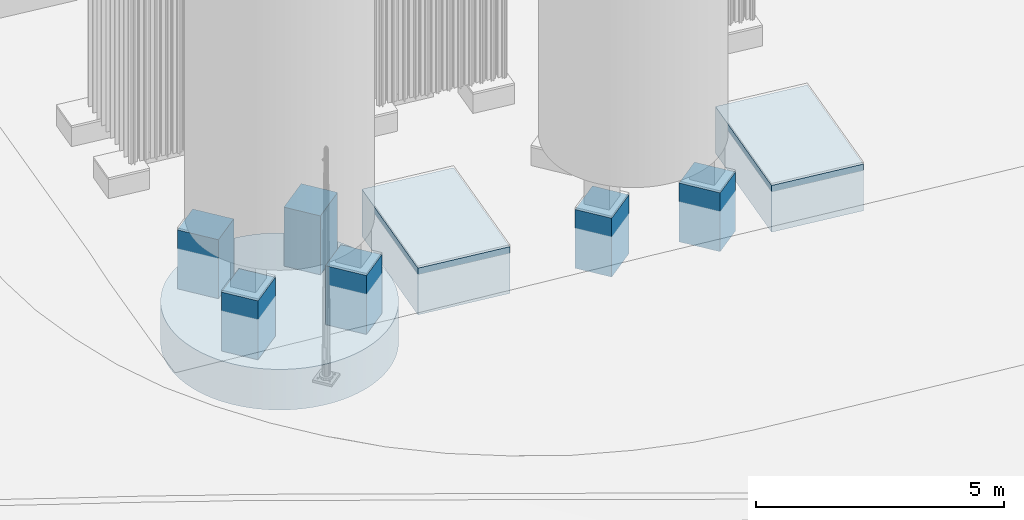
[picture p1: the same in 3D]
Properties of the parts of a building model (IFC4), part 68 of 134

# IfcFooting (214)
Name | In | Description = category = Categoria = Funcion | Document | ExtensionX (m) | ExtensionY (m) | ExtensionZ (m) | SuperficieDeLaMalla (m2) | VolumenGeometrico (m3) | buildingId | buildingName | material | dimensions | JH_InformacionBIM, source = DocumentoFuente | JH_InformacionBIM, status = EstadoDeInformacion | issues = IncidenciasPendientes | positioning = PosicionYEstado | geometryMetrics | materialAppearance | visualizationIdentity | classification | appearance | Volumen geométrico (m³) | JH_Trazabilidad, Material = name | Acabado de visualización = Acabado | Identificador | JH_EvidenciaDeMaterial, source | JH_EvidenciaDeMaterial, status | Perfil | ColorRGB | Rugosidad | Group | Extensión de la malla en X (m) | Extensión de la malla en Y (m) | Extensión de la malla en Z (m) = Espesor o altura real de sección (m) | Cota inferior de visualización (m) | Cota superior de visualización (m) | assemblyId = Conjunto de cimentación | equipmentIds | supportPositionIds | sectionRef = Sección de referencia | sourceCadHandles | stableElementKey | representationKind | geometryStatus | Equipos asociados | Documento de origen | Identificadores CAD de referencia | Cota inferior relativa (m) = Cota inferior relativa adoptada (m) | Cota superior relativa (m) = Cota superior relativa adoptada (m) | Área de planta (m²) | Referencia vertical | Implantación para visualización | Estado de la geometría | Extensión local X (m) | Extensión local Y (m) | Incidencias de origen
Base de autopresurización A · cuerpo de hormigón | Parcela industrial Jinhong | Cimentación industrial | Cimentaciones de equipos y pedestales del fabricante · revisión recibida 04/09/2026 | 2.38997 | 3.24445 | 1.15 | 23.5 | 6.9 | process_plant | Zona de separación de aire | {"name":"Hormigón armado · clase pendiente de confirmar","status":"Clase no confirmada en la hoja de equipo","source":"Geometría de cimentación del fabricante; no se extrapola HA-30 de la nota de pedestales."} | {"documented":[{"label":"Extensión local X","value":2.0,"unit":"m","source":"2593/2596, 2593/E28B, 1FECD","status":"derivada del contorno CAD"},{"label":"Extensión local Y","value":3.0,"unit":"m","source":"2593/2596, 2593/E28B, 1FECD","status":"derivada del contorno CAD"},{"label":"Cota inferior relativa adoptada","value":-1,"unit":"m","source":"7.1–7.1","status":"interpretación con conflicto conservado"},{"label":"Cota superior relativa adoptada","value":0.15000000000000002,"unit":"m","source":"7.1–7.1","status":"documentada / separación por material"}],"geometry":[{"label":"Extensión de la malla en X","value":2.3899740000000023,"unit":"m","source":"Geometría releída del IFC; datum absoluto de proceso provisional","status":"derivado"},{"label":"Extensión de la malla en Y","value":3.2444500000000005,"unit":"m","source":"Geometría releída del IFC; datum absoluto de proceso provisional","status":"derivado"},{"label":"Extensión de la malla en Z","value":1.15,"unit":"m","source":"Geometría releída del IFC; datum absoluto de proceso provisional","status":"derivado"},{"label":"Cota inferior de visualización","value":285.1,"unit":"m","source":"Geometría releída del IFC; datum absoluto de proceso provisional","status":"derivado"},{"label":"Cota superior de visualización","value":286.25,"unit":"m","source":"Geometría releída del IFC; datum absoluto de proceso provisional","status":"derivado"}]} | {"documentId":"LHD2609-JG00100-20260904","title":"Cimentaciones de equipos y pedestales del fabricante · revisión recibida 04/09/2026","date":"2026-09-04","sheet":"7.1–7.1","fileName":"LHD2609-JG00100_20260904.dwg","revisionCaveat":"Fecha de revisión tomada del nombre recibido; cajetines internos mantienen 02/07/2026 y algunos textos de plantilla.","sourceFileSha256":"b42eb027b7bc0b14c38d1d13514f4899b58a732aa8d0ba2ccf10fa2fc3192890"} | provisional | ["El autopresurizador asociado al depósito no tiene objeto de equipo individual en el modelo; esta base no es el apoyo del tanque."] | {"Cota inferior relativa (m)":-1,"Cota superior relativa (m)":0.15000000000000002,"Cero absoluto de visualización (m)":286.1,"Estado del cero absoluto":"Provisional","Criterio":"Las cotas relativas proceden del dibujo; la equivalencia absoluta no está confirmada."} | {"boundingBoxM":{"min":[38.550312,30.428702,0.1],"max":[40.940286,33.673152,1.25]},"extentsM":[2.389974,3.24445,1.15],"meshSurfaceM2":23.5,"meshVolumeM3":6.9,"closedSolid":true,"basis":"Magnitudes de las mallas representadas, no cantidades certificadas de obra, compra o fabricación. Las partes pueden compartir superficies; no se suman como un despiece de materiales."} | {"profileId":"concrete_reinforced","name":"Hormigón armado · gris natural","materialName":"Hormigón armado · clase pendiente de confirmar","physicalMaterialStatus":"Clase no confirmada en la hoja de equipo","physicalMaterialSource":"Geometría de cimentación del fabricante; no se extrapola HA-30 de la nota de pedestales.","appearanceStatus":"criterio_visual","appearanceBasis":"Interpretación visual del material documental; el acabado, tono y parámetros PBR no son una especificación contractual.","note":"La apariencia gráfica no modifica ni confirma la especificación física del material."} | {"elementId":"found_0904_c91a53fc68beda","ifcGuid":"23UJItecXGJhEButZLirP0","ifcClass":"IfcFooting","buildingId":"process_plant","buildingName":"Zona de separación de aire","sourceDocumentId":"LHD2609-JG00100-20260904","sourceRepresentationKind":"foundation"} | {"layerId":"foundations","layerName":"Cimentaciones","role":"Cimentación industrial","basis":"Clasificación por función del elemento; no modifica las especificaciones documentales."} | {"profileId":"concrete_reinforced","name":"Hormigón armado · gris natural","status":"criterio_visual","basis":"Interpretación visual del material documental; el acabado, tono y parámetros PBR no son una especificación contractual.","physicalMaterialUnchanged":true} | 6.9 | Hormigón armado · clase pendiente de confirmar | Hormigón armado · gris natural | found_0904_c91a53fc68beda | Geometría de cimentación del fabricante; no se extrapola HA-30 de la nota de pedestales. | Clase no confirmada en la hoja de equipo | concrete_reinforced | [0.666667,0.662745,0.619608] | 0.96 | Zona de separación de aire; BIM · Cimentaciones | 2.38997 | 3.24445 | 1.15 | 285.1 | 286.25 | F-AUTOPRES-A | [] | [] | 7.1–7.1 | ["2593/2596","2593/E28B","1FECD"] | F-AUTOPRES-A/Base de autopresurización A · cuerpo de hormigón | foundation | Geometría de fabricante; implantación absoluta provisional |  | Cimentaciones de equipos y pedestales del fabricante · revisión recibida 04/09/2026 | 2593/2596, 2593/E28B, 1FECD | -1 | 0.15 | 6 | Cotas relativas del dibujo. La equivalencia con un datum absoluto está pendiente. | Z del modelo = cota relativa + 1,10 m. Correspondencia provisional con 286,10 m; no es cota de obra confirmada. | Sección y contornos del fabricante; incidencias conservadas | 2 | 3 | El autopresurizador asociado al depósito no tiene objeto de equipo individual en el modelo; esta base no es el apoyo del tanque.
Base de autopresurización B · cuerpo de hormigón | Parcela industrial Jinhong | Cimentación industrial | Cimentaciones de equipos y pedestales del fabricante · revisión recibida 04/09/2026 | 2.38997 | 3.24445 | 1.15 | 23.5 | 6.9 | process_plant | Zona de separación de aire | {"name":"Hormigón armado · clase pendiente de confirmar","status":"Clase no confirmada en la hoja de equipo","source":"Geometría de cimentación del fabricante; no se extrapola HA-30 de la nota de pedestales."} | {"documented":[{"label":"Extensión local X","value":2.0,"unit":"m","source":"26E3/2596, 26E3/E28B, 1FECD","status":"derivada del contorno CAD"},{"label":"Extensión local Y","value":3.0,"unit":"m","source":"26E3/2596, 26E3/E28B, 1FECD","status":"derivada del contorno CAD"},{"label":"Cota inferior relativa adoptada","value":-1,"unit":"m","source":"7.1–7.1","status":"interpretación con conflicto conservado"},{"label":"Cota superior relativa adoptada","value":0.15000000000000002,"unit":"m","source":"7.1–7.1","status":"documentada / separación por material"}],"geometry":[{"label":"Extensión de la malla en X","value":2.3899740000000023,"unit":"m","source":"Geometría releída del IFC; datum absoluto de proceso provisional","status":"derivado"},{"label":"Extensión de la malla en Y","value":3.244449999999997,"unit":"m","source":"Geometría releída del IFC; datum absoluto de proceso provisional","status":"derivado"},{"label":"Extensión de la malla en Z","value":1.15,"unit":"m","source":"Geometría releída del IFC; datum absoluto de proceso provisional","status":"derivado"},{"label":"Cota inferior de visualización","value":285.1,"unit":"m","source":"Geometría releída del IFC; datum absoluto de proceso provisional","status":"derivado"},{"label":"Cota superior de visualización","value":286.25,"unit":"m","source":"Geometría releída del IFC; datum absoluto de proceso provisional","status":"derivado"}]} | {"documentId":"LHD2609-JG00100-20260904","title":"Cimentaciones de equipos y pedestales del fabricante · revisión recibida 04/09/2026","date":"2026-09-04","sheet":"7.1–7.1","fileName":"LHD2609-JG00100_20260904.dwg","revisionCaveat":"Fecha de revisión tomada del nombre recibido; cajetines internos mantienen 02/07/2026 y algunos textos de plantilla.","sourceFileSha256":"b42eb027b7bc0b14c38d1d13514f4899b58a732aa8d0ba2ccf10fa2fc3192890"} | provisional | ["El autopresurizador asociado al depósito no tiene objeto de equipo individual en el modelo; esta base no es el apoyo del tanque."] | {"Cota inferior relativa (m)":-1,"Cota superior relativa (m)":0.15000000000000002,"Cero absoluto de visualización (m)":286.1,"Estado del cero absoluto":"Provisional","Criterio":"Las cotas relativas proceden del dibujo; la equivalencia absoluta no está confirmada."} | {"boundingBoxM":{"min":[46.178554,29.379932,0.1],"max":[48.568528,32.624382,1.25]},"extentsM":[2.389974,3.24445,1.15],"meshSurfaceM2":23.500003,"meshVolumeM3":6.900001,"closedSolid":true,"basis":"Magnitudes de las mallas representadas, no cantidades certificadas de obra, compra o fabricación. Las partes pueden compartir superficies; no se suman como un despiece de materiales."} | {"profileId":"concrete_reinforced","name":"Hormigón armado · gris natural","materialName":"Hormigón armado · clase pendiente de confirmar","physicalMaterialStatus":"Clase no confirmada en la hoja de equipo","physicalMaterialSource":"Geometría de cimentación del fabricante; no se extrapola HA-30 de la nota de pedestales.","appearanceStatus":"criterio_visual","appearanceBasis":"Interpretación visual del material documental; el acabado, tono y parámetros PBR no son una especificación contractual.","note":"La apariencia gráfica no modifica ni confirma la especificación física del material."} | {"elementId":"found_0904_9dd31d23571517","ifcGuid":"2T0s$O0W1N$PIk0tDYZWXQ","ifcClass":"IfcFooting","buildingId":"process_plant","buildingName":"Zona de separación de aire","sourceDocumentId":"LHD2609-JG00100-20260904","sourceRepresentationKind":"foundation"} | {"layerId":"foundations","layerName":"Cimentaciones","role":"Cimentación industrial","basis":"Clasificación por función del elemento; no modifica las especificaciones documentales."} | {"profileId":"concrete_reinforced","name":"Hormigón armado · gris natural","status":"criterio_visual","basis":"Interpretación visual del material documental; el acabado, tono y parámetros PBR no son una especificación contractual.","physicalMaterialUnchanged":true} | 6.9 | Hormigón armado · clase pendiente de confirmar | Hormigón armado · gris natural | found_0904_9dd31d23571517 | Geometría de cimentación del fabricante; no se extrapola HA-30 de la nota de pedestales. | Clase no confirmada en la hoja de equipo | concrete_reinforced | [0.666667,0.662745,0.619608] | 0.96 | Zona de separación de aire; BIM · Cimentaciones | 2.38997 | 3.24445 | 1.15 | 285.1 | 286.25 | F-AUTOPRES-B | [] | [] | 7.1–7.1 | ["26E3/2596","26E3/E28B","1FECD"] | F-AUTOPRES-B/Base de autopresurización B · cuerpo de hormigón | foundation | Geometría de fabricante; implantación absoluta provisional |  | Cimentaciones de equipos y pedestales del fabricante · revisión recibida 04/09/2026 | 26E3/2596, 26E3/E28B, 1FECD | -1 | 0.15 | 6 | Cotas relativas del dibujo. La equivalencia con un datum absoluto está pendiente. | Z del modelo = cota relativa + 1,10 m. Correspondencia provisional con 286,10 m; no es cota de obra confirmada. | Sección y contornos del fabricante; incidencias conservadas | 2 | 3 | El autopresurizador asociado al depósito no tiene objeto de equipo individual en el modelo; esta base no es el apoyo del tanque.
Cimentación del vaporizador LV1802A · cuerpo de hormigón | Parcela industrial Jinhong | Cimentación industrial | Cimentaciones de equipos y pedestales del fabricante · revisión recibida 04/09/2026 | 4.45992 | 3.89255 | 0.6 | 36.1428 | 8.17453 | process_plant | Zona de separación de aire | {"name":"Hormigón armado · clase pendiente de confirmar","status":"Clase no confirmada en la hoja de equipo","source":"Geometría de cimentación del fabricante; no se extrapola HA-30 de la nota de pedestales."} | {"documented":[{"label":"Extensión local X","value":4.038,"unit":"m","source":"25A3/25CB, 25A3/E3A8, 1FEC2","status":"derivada del contorno CAD"},{"label":"Extensión local Y","value":3.374,"unit":"m","source":"25A3/25CB, 25A3/E3A8, 1FEC2","status":"derivada del contorno CAD"},{"label":"Cota inferior relativa adoptada","value":-2,"unit":"m","source":"8–8","status":"interpretación con conflicto conservado"},{"label":"Cota superior relativa adoptada","value":-1.4,"unit":"m","source":"8–8","status":"documentada / separación por material"}],"geometry":[{"label":"Extensión de la malla en X","value":4.459921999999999,"unit":"m","source":"Geometría releída del IFC; datum absoluto de proceso provisional","status":"derivado"},{"label":"Extensión de la malla en Y","value":3.892547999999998,"unit":"m","source":"Geometría releída del IFC; datum absoluto de proceso provisional","status":"derivado"},{"label":"Extensión de la malla en Z","value":0.6000000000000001,"unit":"m","source":"Geometría releída del IFC; datum absoluto de proceso provisional","status":"derivado"},{"label":"Cota inferior de visualización","value":284.1,"unit":"m","source":"Geometría releída del IFC; datum absoluto de proceso provisional","status":"derivado"},{"label":"Cota superior de visualización","value":284.7,"unit":"m","source":"Geometría releída del IFC; datum absoluto de proceso provisional","status":"derivado"}]} | {"documentId":"LHD2609-JG00100-20260904","title":"Cimentaciones de equipos y pedestales del fabricante · revisión recibida 04/09/2026","date":"2026-09-04","sheet":"8–8","fileName":"LHD2609-JG00100_20260904.dwg","revisionCaveat":"Fecha de revisión tomada del nombre recibido; cajetines internos mantienen 02/07/2026 y algunos textos de plantilla.","sourceFileSha256":"b42eb027b7bc0b14c38d1d13514f4899b58a732aa8d0ba2ccf10fa2fc3192890"} | provisional | ["Planta: −2,400 m. Sección 8–8: fondo −2,000 m, coronación de losa −1,400 m. Se adopta sección; pendiente de aclaración."] | {"Cota inferior relativa (m)":-2,"Cota superior relativa (m)":-1.4,"Cero absoluto de visualización (m)":286.1,"Estado del cero absoluto":"Provisional","Criterio":"Las cotas relativas proceden del dibujo; la equivalencia absoluta no está confirmada."} | {"boundingBoxM":{"min":[34.134459,35.314695,-0.9],"max":[38.594381,39.207243,-0.3]},"extentsM":[4.459922,3.892548,0.6],"meshSurfaceM2":36.142829,"meshVolumeM3":8.174529,"closedSolid":true,"basis":"Magnitudes de las mallas representadas, no cantidades certificadas de obra, compra o fabricación. Las partes pueden compartir superficies; no se suman como un despiece de materiales."} | {"profileId":"concrete_reinforced","name":"Hormigón armado · gris natural","materialName":"Hormigón armado · clase pendiente de confirmar","physicalMaterialStatus":"Clase no confirmada en la hoja de equipo","physicalMaterialSource":"Geometría de cimentación del fabricante; no se extrapola HA-30 de la nota de pedestales.","appearanceStatus":"criterio_visual","appearanceBasis":"Interpretación visual del material documental; el acabado, tono y parámetros PBR no son una especificación contractual.","note":"La apariencia gráfica no modifica ni confirma la especificación física del material."} | {"elementId":"found_0904_e433e2cc985609","ifcGuid":"1f3MzZfwLSXft64mP6Ilm2","ifcClass":"IfcFooting","buildingId":"process_plant","buildingName":"Zona de separación de aire","sourceDocumentId":"LHD2609-JG00100-20260904","sourceRepresentationKind":"foundation"} | {"layerId":"foundations","layerName":"Cimentaciones","role":"Cimentación industrial","basis":"Clasificación por función del elemento; no modifica las especificaciones documentales."} | {"profileId":"concrete_reinforced","name":"Hormigón armado · gris natural","status":"criterio_visual","basis":"Interpretación visual del material documental; el acabado, tono y parámetros PBR no son una especificación contractual.","physicalMaterialUnchanged":true} | 8.17453 | Hormigón armado · clase pendiente de confirmar | Hormigón armado · gris natural | found_0904_e433e2cc985609 | Geometría de cimentación del fabricante; no se extrapola HA-30 de la nota de pedestales. | Clase no confirmada en la hoja de equipo | concrete_reinforced | [0.666667,0.662745,0.619608] | 0.96 | Zona de separación de aire; BIM · Cimentaciones | 4.45992 | 3.89255 | 0.6 | 284.1 | 284.7 | F-LV1802A | ["LV1802A"] | [] | 8–8 | ["25A3/25CB","25A3/E3A8","1FEC2"] | F-LV1802A/Cimentación del vaporizador LV1802A · cuerpo de hormigón | foundation | Geometría de fabricante; implantación absoluta provisional | LV1802A | Cimentaciones de equipos y pedestales del fabricante · revisión recibida 04/09/2026 | 25A3/25CB, 25A3/E3A8, 1FEC2 | -2 | -1.4 | 13.6242 | Cotas relativas del dibujo. La equivalencia con un datum absoluto está pendiente. | Z del modelo = cota relativa + 1,10 m. Correspondencia provisional con 286,10 m; no es cota de obra confirmada. | Sección y contornos del fabricante; incidencias conservadas | 4.038 | 3.374 | Planta: −2,400 m. Sección 8–8: fondo −2,000 m, coronación de losa −1,400 m. Se adopta sección; pendiente de aclaración.
Cimentación del vaporizador LV1802A · pedestal DZ8 1 | Parcela industrial Jinhong | Cimentación industrial | Cimentaciones de equipos y pedestales del fabricante · revisión recibida 04/09/2026 | 1.00058 | 0.915128 | 1.865 | 7.781 | 1.3428 | process_plant | Zona de separación de aire | {"name":"Hormigón armado · clase pendiente de confirmar","status":"Clase no confirmada en la hoja de equipo","source":"Geometría de cimentación del fabricante; no se extrapola HA-30 de la nota de pedestales."} | {"documented":[{"label":"Extensión local X","value":0.9,"unit":"m","source":"25A3/25CB, 25A3/E3A8, 1FEC2","status":"derivada del contorno CAD"},{"label":"Extensión local Y","value":0.8,"unit":"m","source":"25A3/25CB, 25A3/E3A8, 1FEC2","status":"derivada del contorno CAD"},{"label":"Cota inferior relativa adoptada","value":-1.4,"unit":"m","source":"8–8","status":"interpretación con conflicto conservado"},{"label":"Cota superior relativa adoptada","value":0.465,"unit":"m","source":"8–8","status":"documentada / separación por material"}],"geometry":[{"label":"Extensión de la malla en X","value":1.0005760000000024,"unit":"m","source":"Geometría releída del IFC; datum absoluto de proceso provisional","status":"derivado"},{"label":"Extensión de la malla en Y","value":0.9151279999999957,"unit":"m","source":"Geometría releída del IFC; datum absoluto de proceso provisional","status":"derivado"},{"label":"Extensión de la malla en Z","value":1.865,"unit":"m","source":"Geometría releída del IFC; datum absoluto de proceso provisional","status":"derivado"},{"label":"Cota inferior de visualización","value":284.7,"unit":"m","source":"Geometría releída del IFC; datum absoluto de proceso provisional","status":"derivado"},{"label":"Cota superior de visualización","value":286.565,"unit":"m","source":"Geometría releída del IFC; datum absoluto de proceso provisional","status":"derivado"}]} | {"documentId":"LHD2609-JG00100-20260904","title":"Cimentaciones de equipos y pedestales del fabricante · revisión recibida 04/09/2026","date":"2026-09-04","sheet":"8–8","fileName":"LHD2609-JG00100_20260904.dwg","revisionCaveat":"Fecha de revisión tomada del nombre recibido; cajetines internos mantienen 02/07/2026 y algunos textos de plantilla.","sourceFileSha256":"b42eb027b7bc0b14c38d1d13514f4899b58a732aa8d0ba2ccf10fa2fc3192890"} | provisional | ["Planta: −2,400 m. Sección 8–8: fondo −2,000 m, coronación de losa −1,400 m. Se adopta sección; pendiente de aclaración."] | {"Cota inferior relativa (m)":-1.4,"Cota superior relativa (m)":0.465,"Cero absoluto de visualización (m)":286.1,"Estado del cero absoluto":"Provisional","Criterio":"Las cotas relativas proceden del dibujo; la equivalencia absoluta no está confirmada."} | {"boundingBoxM":{"min":[34.741391,37.95405,-0.3],"max":[35.741967,38.869178,1.565]},"extentsM":[1.000576,0.915128,1.865],"meshSurfaceM2":7.781,"meshVolumeM3":1.3428,"closedSolid":true,"basis":"Magnitudes de las mallas representadas, no cantidades certificadas de obra, compra o fabricación. Las partes pueden compartir superficies; no se suman como un despiece de materiales."} | {"profileId":"concrete_reinforced","name":"Hormigón armado · gris natural","materialName":"Hormigón armado · clase pendiente de confirmar","physicalMaterialStatus":"Clase no confirmada en la hoja de equipo","physicalMaterialSource":"Geometría de cimentación del fabricante; no se extrapola HA-30 de la nota de pedestales.","appearanceStatus":"criterio_visual","appearanceBasis":"Interpretación visual del material documental; el acabado, tono y parámetros PBR no son una especificación contractual.","note":"La apariencia gráfica no modifica ni confirma la especificación física del material."} | {"elementId":"found_0904_b11f1428c835a3","ifcGuid":"1dzepKsrTO0B1ccf4_R9Bp","ifcClass":"IfcFooting","buildingId":"process_plant","buildingName":"Zona de separación de aire","sourceDocumentId":"LHD2609-JG00100-20260904","sourceRepresentationKind":"foundation"} | {"layerId":"foundations","layerName":"Cimentaciones","role":"Cimentación industrial","basis":"Clasificación por función del elemento; no modifica las especificaciones documentales."} | {"profileId":"concrete_reinforced","name":"Hormigón armado · gris natural","status":"criterio_visual","basis":"Interpretación visual del material documental; el acabado, tono y parámetros PBR no son una especificación contractual.","physicalMaterialUnchanged":true} | 1.3428 | Hormigón armado · clase pendiente de confirmar | Hormigón armado · gris natural | found_0904_b11f1428c835a3 | Geometría de cimentación del fabricante; no se extrapola HA-30 de la nota de pedestales. | Clase no confirmada en la hoja de equipo | concrete_reinforced | [0.666667,0.662745,0.619608] | 0.96 | Zona de separación de aire; BIM · Cimentaciones | 1.00058 | 0.915128 | 1.865 | 284.7 | 286.565 | F-LV1802A | ["LV1802A"] | [] | 8–8 | ["25A3/25CB","25A3/E3A8","1FEC2"] | F-LV1802A/Cimentación del vaporizador LV1802A · pedestal DZ8 1 | foundation | Geometría de fabricante; implantación absoluta provisional | LV1802A | Cimentaciones de equipos y pedestales del fabricante · revisión recibida 04/09/2026 | 25A3/25CB, 25A3/E3A8, 1FEC2 | -1.4 | 0.465 | 0.72 | Cotas relativas del dibujo. La equivalencia con un datum absoluto está pendiente. | Z del modelo = cota relativa + 1,10 m. Correspondencia provisional con 286,10 m; no es cota de obra confirmada. | Sección y contornos del fabricante; incidencias conservadas | 0.9 | 0.8 | Planta: −2,400 m. Sección 8–8: fondo −2,000 m, coronación de losa −1,400 m. Se adopta sección; pendiente de aclaración.
Cimentación del vaporizador LV1802A · pedestal DZ8 2 | Parcela industrial Jinhong | Cimentación industrial | Cimentaciones de equipos y pedestales del fabricante · revisión recibida 04/09/2026 | 1.00058 | 0.915128 | 1.865 | 7.781 | 1.3428 | process_plant | Zona de separación de aire | {"name":"Hormigón armado · clase pendiente de confirmar","status":"Clase no confirmada en la hoja de equipo","source":"Geometría de cimentación del fabricante; no se extrapola HA-30 de la nota de pedestales."} | {"documented":[{"label":"Extensión local X","value":0.9,"unit":"m","source":"25A3/25CB, 25A3/E3A8, 1FEC2","status":"derivada del contorno CAD"},{"label":"Extensión local Y","value":0.8,"unit":"m","source":"25A3/25CB, 25A3/E3A8, 1FEC2","status":"derivada del contorno CAD"},{"label":"Cota inferior relativa adoptada","value":-1.4,"unit":"m","source":"8–8","status":"interpretación con conflicto conservado"},{"label":"Cota superior relativa adoptada","value":0.465,"unit":"m","source":"8–8","status":"documentada / separación por material"}],"geometry":[{"label":"Extensión de la malla en X","value":1.0005760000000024,"unit":"m","source":"Geometría releída del IFC; datum absoluto de proceso provisional","status":"derivado"},{"label":"Extensión de la malla en Y","value":0.9151279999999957,"unit":"m","source":"Geometría releída del IFC; datum absoluto de proceso provisional","status":"derivado"},{"label":"Extensión de la malla en Z","value":1.865,"unit":"m","source":"Geometría releída del IFC; datum absoluto de proceso provisional","status":"derivado"},{"label":"Cota inferior de visualización","value":284.7,"unit":"m","source":"Geometría releída del IFC; datum absoluto de proceso provisional","status":"derivado"},{"label":"Cota superior de visualización","value":286.565,"unit":"m","source":"Geometría releída del IFC; datum absoluto de proceso provisional","status":"derivado"}]} | {"documentId":"LHD2609-JG00100-20260904","title":"Cimentaciones de equipos y pedestales del fabricante · revisión recibida 04/09/2026","date":"2026-09-04","sheet":"8–8","fileName":"LHD2609-JG00100_20260904.dwg","revisionCaveat":"Fecha de revisión tomada del nombre recibido; cajetines internos mantienen 02/07/2026 y algunos textos de plantilla.","sourceFileSha256":"b42eb027b7bc0b14c38d1d13514f4899b58a732aa8d0ba2ccf10fa2fc3192890"} | provisional | ["Planta: −2,400 m. Sección 8–8: fondo −2,000 m, coronación de losa −1,400 m. Se adopta sección; pendiente de aclaración."] | {"Cota inferior relativa (m)":-1.4,"Cota superior relativa (m)":0.465,"Cero absoluto de visualización (m)":286.1,"Estado del cero absoluto":"Provisional","Criterio":"Las cotas relativas proceden del dibujo; la equivalencia absoluta no está confirmada."} | {"boundingBoxM":{"min":[37.255739,37.608364,-0.3],"max":[38.256315,38.523492,1.565]},"extentsM":[1.000576,0.915128,1.865],"meshSurfaceM2":7.781,"meshVolumeM3":1.3428,"closedSolid":true,"basis":"Magnitudes de las mallas representadas, no cantidades certificadas de obra, compra o fabricación. Las partes pueden compartir superficies; no se suman como un despiece de materiales."} | {"profileId":"concrete_reinforced","name":"Hormigón armado · gris natural","materialName":"Hormigón armado · clase pendiente de confirmar","physicalMaterialStatus":"Clase no confirmada en la hoja de equipo","physicalMaterialSource":"Geometría de cimentación del fabricante; no se extrapola HA-30 de la nota de pedestales.","appearanceStatus":"criterio_visual","appearanceBasis":"Interpretación visual del material documental; el acabado, tono y parámetros PBR no son una especificación contractual.","note":"La apariencia gráfica no modifica ni confirma la especificación física del material."} | {"elementId":"found_0904_a83674f38876df","ifcGuid":"2RRTFUkqjQBvFSGXaSZmnt","ifcClass":"IfcFooting","buildingId":"process_plant","buildingName":"Zona de separación de aire","sourceDocumentId":"LHD2609-JG00100-20260904","sourceRepresentationKind":"foundation"} | {"layerId":"foundations","layerName":"Cimentaciones","role":"Cimentación industrial","basis":"Clasificación por función del elemento; no modifica las especificaciones documentales."} | {"profileId":"concrete_reinforced","name":"Hormigón armado · gris natural","status":"criterio_visual","basis":"Interpretación visual del material documental; el acabado, tono y parámetros PBR no son una especificación contractual.","physicalMaterialUnchanged":true} | 1.3428 | Hormigón armado · clase pendiente de confirmar | Hormigón armado · gris natural | found_0904_a83674f38876df | Geometría de cimentación del fabricante; no se extrapola HA-30 de la nota de pedestales. | Clase no confirmada en la hoja de equipo | concrete_reinforced | [0.666667,0.662745,0.619608] | 0.96 | Zona de separación de aire; BIM · Cimentaciones | 1.00058 | 0.915128 | 1.865 | 284.7 | 286.565 | F-LV1802A | ["LV1802A"] | [] | 8–8 | ["25A3/25CB","25A3/E3A8","1FEC2"] | F-LV1802A/Cimentación del vaporizador LV1802A · pedestal DZ8 2 | foundation | Geometría de fabricante; implantación absoluta provisional | LV1802A | Cimentaciones de equipos y pedestales del fabricante · revisión recibida 04/09/2026 | 25A3/25CB, 25A3/E3A8, 1FEC2 | -1.4 | 0.465 | 0.72 | Cotas relativas del dibujo. La equivalencia con un datum absoluto está pendiente. | Z del modelo = cota relativa + 1,10 m. Correspondencia provisional con 286,10 m; no es cota de obra confirmada. | Sección y contornos del fabricante; incidencias conservadas | 0.9 | 0.8 | Planta: −2,400 m. Sección 8–8: fondo −2,000 m, coronación de losa −1,400 m. Se adopta sección; pendiente de aclaración.
Cimentación del vaporizador LV1802A · pedestal DZ8 3 | Parcela industrial Jinhong | Cimentación industrial | Cimentaciones de equipos y pedestales del fabricante · revisión recibida 04/09/2026 | 1.00058 | 0.915129 | 1.865 | 7.781 | 1.3428 | process_plant | Zona de separación de aire | {"name":"Hormigón armado · clase pendiente de confirmar","status":"Clase no confirmada en la hoja de equipo","source":"Geometría de cimentación del fabricante; no se extrapola HA-30 de la nota de pedestales."} | {"documented":[{"label":"Extensión local X","value":0.9,"unit":"m","source":"25A3/25CB, 25A3/E3A8, 1FEC2","status":"derivada del contorno CAD"},{"label":"Extensión local Y","value":0.8,"unit":"m","source":"25A3/25CB, 25A3/E3A8, 1FEC2","status":"derivada del contorno CAD"},{"label":"Cota inferior relativa adoptada","value":-1.4,"unit":"m","source":"8–8","status":"interpretación con conflicto conservado"},{"label":"Cota superior relativa adoptada","value":0.465,"unit":"m","source":"8–8","status":"documentada / separación por material"}],"geometry":[{"label":"Extensión de la malla en X","value":1.0005759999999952,"unit":"m","source":"Geometría releída del IFC; datum absoluto de proceso provisional","status":"derivado"},{"label":"Extensión de la malla en Y","value":0.9151290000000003,"unit":"m","source":"Geometría releída del IFC; datum absoluto de proceso provisional","status":"derivado"},{"label":"Extensión de la malla en Z","value":1.865,"unit":"m","source":"Geometría releída del IFC; datum absoluto de proceso provisional","status":"derivado"},{"label":"Cota inferior de visualización","value":284.7,"unit":"m","source":"Geometría releída del IFC; datum absoluto de proceso provisional","status":"derivado"},{"label":"Cota superior de visualización","value":286.565,"unit":"m","source":"Geometría releída del IFC; datum absoluto de proceso provisional","status":"derivado"}]} | {"documentId":"LHD2609-JG00100-20260904","title":"Cimentaciones de equipos y pedestales del fabricante · revisión recibida 04/09/2026","date":"2026-09-04","sheet":"8–8","fileName":"LHD2609-JG00100_20260904.dwg","revisionCaveat":"Fecha de revisión tomada del nombre recibido; cajetines internos mantienen 02/07/2026 y algunos textos de plantilla.","sourceFileSha256":"b42eb027b7bc0b14c38d1d13514f4899b58a732aa8d0ba2ccf10fa2fc3192890"} | provisional | ["Planta: −2,400 m. Sección 8–8: fondo −2,000 m, coronación de losa −1,400 m. Se adopta sección; pendiente de aclaración."] | {"Cota inferior relativa (m)":-1.4,"Cota superior relativa (m)":0.465,"Cero absoluto de visualización (m)":286.1,"Estado del cero absoluto":"Provisional","Criterio":"Las cotas relativas proceden del dibujo; la equivalencia absoluta no está confirmada."} | {"boundingBoxM":{"min":[36.986873,35.65276,-0.3],"max":[37.987449,36.567889,1.565]},"extentsM":[1.000576,0.915129,1.865],"meshSurfaceM2":7.781003,"meshVolumeM3":1.342801,"closedSolid":true,"basis":"Magnitudes de las mallas representadas, no cantidades certificadas de obra, compra o fabricación. Las partes pueden compartir superficies; no se suman como un despiece de materiales."} | {"profileId":"concrete_reinforced","name":"Hormigón armado · gris natural","materialName":"Hormigón armado · clase pendiente de confirmar","physicalMaterialStatus":"Clase no confirmada en la hoja de equipo","physicalMaterialSource":"Geometría de cimentación del fabricante; no se extrapola HA-30 de la nota de pedestales.","appearanceStatus":"criterio_visual","appearanceBasis":"Interpretación visual del material documental; el acabado, tono y parámetros PBR no son una especificación contractual.","note":"La apariencia gráfica no modifica ni confirma la especificación física del material."} | {"elementId":"found_0904_7bd630c6b96de3","ifcGuid":"14jjNZLCzTQfjYo5m27AEY","ifcClass":"IfcFooting","buildingId":"process_plant","buildingName":"Zona de separación de aire","sourceDocumentId":"LHD2609-JG00100-20260904","sourceRepresentationKind":"foundation"} | {"layerId":"foundations","layerName":"Cimentaciones","role":"Cimentación industrial","basis":"Clasificación por función del elemento; no modifica las especificaciones documentales."} | {"profileId":"concrete_reinforced","name":"Hormigón armado · gris natural","status":"criterio_visual","basis":"Interpretación visual del material documental; el acabado, tono y parámetros PBR no son una especificación contractual.","physicalMaterialUnchanged":true} | 1.3428 | Hormigón armado · clase pendiente de confirmar | Hormigón armado · gris natural | found_0904_7bd630c6b96de3 | Geometría de cimentación del fabricante; no se extrapola HA-30 de la nota de pedestales. | Clase no confirmada en la hoja de equipo | concrete_reinforced | [0.666667,0.662745,0.619608] | 0.96 | Zona de separación de aire; BIM · Cimentaciones | 1.00058 | 0.915129 | 1.865 | 284.7 | 286.565 | F-LV1802A | ["LV1802A"] | [] | 8–8 | ["25A3/25CB","25A3/E3A8","1FEC2"] | F-LV1802A/Cimentación del vaporizador LV1802A · pedestal DZ8 3 | foundation | Geometría de fabricante; implantación absoluta provisional | LV1802A | Cimentaciones de equipos y pedestales del fabricante · revisión recibida 04/09/2026 | 25A3/25CB, 25A3/E3A8, 1FEC2 | -1.4 | 0.465 | 0.72 | Cotas relativas del dibujo. La equivalencia con un datum absoluto está pendiente. | Z del modelo = cota relativa + 1,10 m. Correspondencia provisional con 286,10 m; no es cota de obra confirmada. | Sección y contornos del fabricante; incidencias conservadas | 0.9 | 0.8 | Planta: −2,400 m. Sección 8–8: fondo −2,000 m, coronación de losa −1,400 m. Se adopta sección; pendiente de aclaración.
Cimentación del vaporizador LV1802A · pedestal DZ8 4 | Parcela industrial Jinhong | Cimentación industrial | Cimentaciones de equipos y pedestales del fabricante · revisión recibida 04/09/2026 | 1.00058 | 0.915128 | 1.865 | 7.781 | 1.3428 | process_plant | Zona de separación de aire | {"name":"Hormigón armado · clase pendiente de confirmar","status":"Clase no confirmada en la hoja de equipo","source":"Geometría de cimentación del fabricante; no se extrapola HA-30 de la nota de pedestales."} | {"documented":[{"label":"Extensión local X","value":0.9,"unit":"m","source":"25A3/25CB, 25A3/E3A8, 1FEC2","status":"derivada del contorno CAD"},{"label":"Extensión local Y","value":0.8,"unit":"m","source":"25A3/25CB, 25A3/E3A8, 1FEC2","status":"derivada del contorno CAD"},{"label":"Cota inferior relativa adoptada","value":-1.4,"unit":"m","source":"8–8","status":"interpretación con conflicto conservado"},{"label":"Cota superior relativa adoptada","value":0.465,"unit":"m","source":"8–8","status":"documentada / separación por material"}],"geometry":[{"label":"Extensión de la malla en X","value":1.0005760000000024,"unit":"m","source":"Geometría releída del IFC; datum absoluto de proceso provisional","status":"derivado"},{"label":"Extensión de la malla en Y","value":0.9151279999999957,"unit":"m","source":"Geometría releída del IFC; datum absoluto de proceso provisional","status":"derivado"},{"label":"Extensión de la malla en Z","value":1.865,"unit":"m","source":"Geometría releída del IFC; datum absoluto de proceso provisional","status":"derivado"},{"label":"Cota inferior de visualización","value":284.7,"unit":"m","source":"Geometría releída del IFC; datum absoluto de proceso provisional","status":"derivado"},{"label":"Cota superior de visualización","value":286.565,"unit":"m","source":"Geometría releída del IFC; datum absoluto de proceso provisional","status":"derivado"}]} | {"documentId":"LHD2609-JG00100-20260904","title":"Cimentaciones de equipos y pedestales del fabricante · revisión recibida 04/09/2026","date":"2026-09-04","sheet":"8–8","fileName":"LHD2609-JG00100_20260904.dwg","revisionCaveat":"Fecha de revisión tomada del nombre recibido; cajetines internos mantienen 02/07/2026 y algunos textos de plantilla.","sourceFileSha256":"b42eb027b7bc0b14c38d1d13514f4899b58a732aa8d0ba2ccf10fa2fc3192890"} | provisional | ["Planta: −2,400 m. Sección 8–8: fondo −2,000 m, coronación de losa −1,400 m. Se adopta sección; pendiente de aclaración."] | {"Cota inferior relativa (m)":-1.4,"Cota superior relativa (m)":0.465,"Cero absoluto de visualización (m)":286.1,"Estado del cero absoluto":"Provisional","Criterio":"Las cotas relativas proceden del dibujo; la equivalencia absoluta no está confirmada."} | {"boundingBoxM":{"min":[34.472525,35.998446,-0.3],"max":[35.473101,36.913574,1.565]},"extentsM":[1.000576,0.915128,1.865],"meshSurfaceM2":7.781003,"meshVolumeM3":1.342801,"closedSolid":true,"basis":"Magnitudes de las mallas representadas, no cantidades certificadas de obra, compra o fabricación. Las partes pueden compartir superficies; no se suman como un despiece de materiales."} | {"profileId":"concrete_reinforced","name":"Hormigón armado · gris natural","materialName":"Hormigón armado · clase pendiente de confirmar","physicalMaterialStatus":"Clase no confirmada en la hoja de equipo","physicalMaterialSource":"Geometría de cimentación del fabricante; no se extrapola HA-30 de la nota de pedestales.","appearanceStatus":"criterio_visual","appearanceBasis":"Interpretación visual del material documental; el acabado, tono y parámetros PBR no son una especificación contractual.","note":"La apariencia gráfica no modifica ni confirma la especificación física del material."} | {"elementId":"found_0904_24789a3e32a652","ifcGuid":"0OaZGgeF1UgxI9RO$izC_0","ifcClass":"IfcFooting","buildingId":"process_plant","buildingName":"Zona de separación de aire","sourceDocumentId":"LHD2609-JG00100-20260904","sourceRepresentationKind":"foundation"} | {"layerId":"foundations","layerName":"Cimentaciones","role":"Cimentación industrial","basis":"Clasificación por función del elemento; no modifica las especificaciones documentales."} | {"profileId":"concrete_reinforced","name":"Hormigón armado · gris natural","status":"criterio_visual","basis":"Interpretación visual del material documental; el acabado, tono y parámetros PBR no son una especificación contractual.","physicalMaterialUnchanged":true} | 1.3428 | Hormigón armado · clase pendiente de confirmar | Hormigón armado · gris natural | found_0904_24789a3e32a652 | Geometría de cimentación del fabricante; no se extrapola HA-30 de la nota de pedestales. | Clase no confirmada en la hoja de equipo | concrete_reinforced | [0.666667,0.662745,0.619608] | 0.96 | Zona de separación de aire; BIM · Cimentaciones | 1.00058 | 0.915128 | 1.865 | 284.7 | 286.565 | F-LV1802A | ["LV1802A"] | [] | 8–8 | ["25A3/25CB","25A3/E3A8","1FEC2"] | F-LV1802A/Cimentación del vaporizador LV1802A · pedestal DZ8 4 | foundation | Geometría de fabricante; implantación absoluta provisional | LV1802A | Cimentaciones de equipos y pedestales del fabricante · revisión recibida 04/09/2026 | 25A3/25CB, 25A3/E3A8, 1FEC2 | -1.4 | 0.465 | 0.72 | Cotas relativas del dibujo. La equivalencia con un datum absoluto está pendiente. | Z del modelo = cota relativa + 1,10 m. Correspondencia provisional con 286,10 m; no es cota de obra confirmada. | Sección y contornos del fabricante; incidencias conservadas | 0.9 | 0.8 | Planta: −2,400 m. Sección 8–8: fondo −2,000 m, coronación de losa −1,400 m. Se adopta sección; pendiente de aclaración.
Cimentación del vaporizador LV1802A · pedestal DZ8 5 | Parcela industrial Jinhong | Cimentación industrial | Cimentaciones de equipos y pedestales del fabricante · revisión recibida 04/09/2026 | 1.00058 | 0.915128 | 1.865 | 7.781 | 1.3428 | process_plant | Zona de separación de aire | {"name":"Hormigón armado · clase pendiente de confirmar","status":"Clase no confirmada en la hoja de equipo","source":"Geometría de cimentación del fabricante; no se extrapola HA-30 de la nota de pedestales."} | {"documented":[{"label":"Extensión local X","value":0.9,"unit":"m","source":"25A3/25CB, 25A3/E3A8, 1FEC2","status":"derivada del contorno CAD"},{"label":"Extensión local Y","value":0.8,"unit":"m","source":"25A3/25CB, 25A3/E3A8, 1FEC2","status":"derivada del contorno CAD"},{"label":"Cota inferior relativa adoptada","value":-1.4,"unit":"m","source":"8–8","status":"interpretación con conflicto conservado"},{"label":"Cota superior relativa adoptada","value":0.465,"unit":"m","source":"8–8","status":"documentada / separación por material"}],"geometry":[{"label":"Extensión de la malla en X","value":1.0005760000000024,"unit":"m","source":"Geometría releída del IFC; datum absoluto de proceso provisional","status":"derivado"},{"label":"Extensión de la malla en Y","value":0.9151280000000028,"unit":"m","source":"Geometría releída del IFC; datum absoluto de proceso provisional","status":"derivado"},{"label":"Extensión de la malla en Z","value":1.865,"unit":"m","source":"Geometría releída del IFC; datum absoluto de proceso provisional","status":"derivado"},{"label":"Cota inferior de visualización","value":284.7,"unit":"m","source":"Geometría releída del IFC; datum absoluto de proceso provisional","status":"derivado"},{"label":"Cota superior de visualización","value":286.565,"unit":"m","source":"Geometría releída del IFC; datum absoluto de proceso provisional","status":"derivado"}]} | {"documentId":"LHD2609-JG00100-20260904","title":"Cimentaciones de equipos y pedestales del fabricante · revisión recibida 04/09/2026","date":"2026-09-04","sheet":"8–8","fileName":"LHD2609-JG00100_20260904.dwg","revisionCaveat":"Fecha de revisión tomada del nombre recibido; cajetines internos mantienen 02/07/2026 y algunos textos de plantilla.","sourceFileSha256":"b42eb027b7bc0b14c38d1d13514f4899b58a732aa8d0ba2ccf10fa2fc3192890"} | provisional | ["Planta: −2,400 m. Sección 8–8: fondo −2,000 m, coronación de losa −1,400 m. Se adopta sección; pendiente de aclaración."] | {"Cota inferior relativa (m)":-1.4,"Cota superior relativa (m)":0.465,"Cero absoluto de visualización (m)":286.1,"Estado del cero absoluto":"Provisional","Criterio":"Las cotas relativas proceden del dibujo; la equivalencia absoluta no está confirmada."} | {"boundingBoxM":{"min":[35.705241,36.682924,-0.3],"max":[36.705817,37.598052,1.565]},"extentsM":[1.000576,0.915128,1.865],"meshSurfaceM2":7.781003,"meshVolumeM3":1.342801,"closedSolid":true,"basis":"Magnitudes de las mallas representadas, no cantidades certificadas de obra, compra o fabricación. Las partes pueden compartir superficies; no se suman como un despiece de materiales."} | {"profileId":"concrete_reinforced","name":"Hormigón armado · gris natural","materialName":"Hormigón armado · clase pendiente de confirmar","physicalMaterialStatus":"Clase no confirmada en la hoja de equipo","physicalMaterialSource":"Geometría de cimentación del fabricante; no se extrapola HA-30 de la nota de pedestales.","appearanceStatus":"criterio_visual","appearanceBasis":"Interpretación visual del material documental; el acabado, tono y parámetros PBR no son una especificación contractual.","note":"La apariencia gráfica no modifica ni confirma la especificación física del material."} | {"elementId":"found_0904_4b669e04c54a89","ifcGuid":"3YqeQNtMPKDP6f_G3zuE6C","ifcClass":"IfcFooting","buildingId":"process_plant","buildingName":"Zona de separación de aire","sourceDocumentId":"LHD2609-JG00100-20260904","sourceRepresentationKind":"foundation"} | {"layerId":"foundations","layerName":"Cimentaciones","role":"Cimentación industrial","basis":"Clasificación por función del elemento; no modifica las especificaciones documentales."} | {"profileId":"concrete_reinforced","name":"Hormigón armado · gris natural","status":"criterio_visual","basis":"Interpretación visual del material documental; el acabado, tono y parámetros PBR no son una especificación contractual.","physicalMaterialUnchanged":true} | 1.3428 | Hormigón armado · clase pendiente de confirmar | Hormigón armado · gris natural | found_0904_4b669e04c54a89 | Geometría de cimentación del fabricante; no se extrapola HA-30 de la nota de pedestales. | Clase no confirmada en la hoja de equipo | concrete_reinforced | [0.666667,0.662745,0.619608] | 0.96 | Zona de separación de aire; BIM · Cimentaciones | 1.00058 | 0.915128 | 1.865 | 284.7 | 286.565 | F-LV1802A | ["LV1802A"] | [] | 8–8 | ["25A3/25CB","25A3/E3A8","1FEC2"] | F-LV1802A/Cimentación del vaporizador LV1802A · pedestal DZ8 5 | foundation | Geometría de fabricante; implantación absoluta provisional | LV1802A | Cimentaciones de equipos y pedestales del fabricante · revisión recibida 04/09/2026 | 25A3/25CB, 25A3/E3A8, 1FEC2 | -1.4 | 0.465 | 0.72 | Cotas relativas del dibujo. La equivalencia con un datum absoluto está pendiente. | Z del modelo = cota relativa + 1,10 m. Correspondencia provisional con 286,10 m; no es cota de obra confirmada. | Sección y contornos del fabricante; incidencias conservadas | 0.9 | 0.8 | Planta: −2,400 m. Sección 8–8: fondo −2,000 m, coronación de losa −1,400 m. Se adopta sección; pendiente de aclaración.
Cimentación del vaporizador LV1802B · cuerpo de hormigón | Parcela industrial Jinhong | Cimentación industrial | Cimentaciones de equipos y pedestales del fabricante · revisión recibida 04/09/2026 | 4.45992 | 3.89255 | 0.6 | 36.1428 | 8.17453 | process_plant | Zona de separación de aire | {"name":"Hormigón armado · clase pendiente de confirmar","status":"Clase no confirmada en la hoja de equipo","source":"Geometría de cimentación del fabricante; no se extrapola HA-30 de la nota de pedestales."} | {"documented":[{"label":"Extensión local X","value":4.038,"unit":"m","source":"2718/25CB, 2718/E3A8, 1FEC2","status":"derivada del contorno CAD"},{"label":"Extensión local Y","value":3.374,"unit":"m","source":"2718/25CB, 2718/E3A8, 1FEC2","status":"derivada del contorno CAD"},{"label":"Cota inferior relativa adoptada","value":-2,"unit":"m","source":"8–8","status":"interpretación con conflicto conservado"},{"label":"Cota superior relativa adoptada","value":-1.4,"unit":"m","source":"8–8","status":"documentada / separación por material"}],"geometry":[{"label":"Extensión de la malla en X","value":4.459921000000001,"unit":"m","source":"Geometría releída del IFC; datum absoluto de proceso provisional","status":"derivado"},{"label":"Extensión de la malla en Y","value":3.892547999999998,"unit":"m","source":"Geometría releída del IFC; datum absoluto de proceso provisional","status":"derivado"},{"label":"Extensión de la malla en Z","value":0.6000000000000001,"unit":"m","source":"Geometría releída del IFC; datum absoluto de proceso provisional","status":"derivado"},{"label":"Cota inferior de visualización","value":284.1,"unit":"m","source":"Geometría releída del IFC; datum absoluto de proceso provisional","status":"derivado"},{"label":"Cota superior de visualización","value":284.7,"unit":"m","source":"Geometría releída del IFC; datum absoluto de proceso provisional","status":"derivado"}]} | {"documentId":"LHD2609-JG00100-20260904","title":"Cimentaciones de equipos y pedestales del fabricante · revisión recibida 04/09/2026","date":"2026-09-04","sheet":"8–8","fileName":"LHD2609-JG00100_20260904.dwg","revisionCaveat":"Fecha de revisión tomada del nombre recibido; cajetines internos mantienen 02/07/2026 y algunos textos de plantilla.","sourceFileSha256":"b42eb027b7bc0b14c38d1d13514f4899b58a732aa8d0ba2ccf10fa2fc3192890"} | provisional | ["Planta: −2,400 m. Sección 8–8: fondo −2,000 m, coronación de losa −1,400 m. Se adopta sección; pendiente de aclaración."] | {"Cota inferior relativa (m)":-2,"Cota superior relativa (m)":-1.4,"Cero absoluto de visualización (m)":286.1,"Estado del cero absoluto":"Provisional","Criterio":"Las cotas relativas proceden del dibujo; la equivalencia absoluta no está confirmada."} | {"boundingBoxM":{"min":[39.484136,34.579194,-0.9],"max":[43.944057,38.471742,-0.3]},"extentsM":[4.459921,3.892548,0.6],"meshSurfaceM2":36.142821,"meshVolumeM3":8.174527,"closedSolid":true,"basis":"Magnitudes de las mallas representadas, no cantidades certificadas de obra, compra o fabricación. Las partes pueden compartir superficies; no se suman como un despiece de materiales."} | {"profileId":"concrete_reinforced","name":"Hormigón armado · gris natural","materialName":"Hormigón armado · clase pendiente de confirmar","physicalMaterialStatus":"Clase no confirmada en la hoja de equipo","physicalMaterialSource":"Geometría de cimentación del fabricante; no se extrapola HA-30 de la nota de pedestales.","appearanceStatus":"criterio_visual","appearanceBasis":"Interpretación visual del material documental; el acabado, tono y parámetros PBR no son una especificación contractual.","note":"La apariencia gráfica no modifica ni confirma la especificación física del material."} | {"elementId":"found_0904_d0f045b5660f21","ifcGuid":"0qrgQwhc1POvJhZBTTA$2v","ifcClass":"IfcFooting","buildingId":"process_plant","buildingName":"Zona de separación de aire","sourceDocumentId":"LHD2609-JG00100-20260904","sourceRepresentationKind":"foundation"} | {"layerId":"foundations","layerName":"Cimentaciones","role":"Cimentación industrial","basis":"Clasificación por función del elemento; no modifica las especificaciones documentales."} | {"profileId":"concrete_reinforced","name":"Hormigón armado · gris natural","status":"criterio_visual","basis":"Interpretación visual del material documental; el acabado, tono y parámetros PBR no son una especificación contractual.","physicalMaterialUnchanged":true} | 8.17453 | Hormigón armado · clase pendiente de confirmar | Hormigón armado · gris natural | found_0904_d0f045b5660f21 | Geometría de cimentación del fabricante; no se extrapola HA-30 de la nota de pedestales. | Clase no confirmada en la hoja de equipo | concrete_reinforced | [0.666667,0.662745,0.619608] | 0.96 | Zona de separación de aire; BIM · Cimentaciones | 4.45992 | 3.89255 | 0.6 | 284.1 | 284.7 | F-LV1802B | ["LV1802B"] | [] | 8–8 | ["2718/25CB","2718/E3A8","1FEC2"] | F-LV1802B/Cimentación del vaporizador LV1802B · cuerpo de hormigón | foundation | Geometría de fabricante; implantación absoluta provisional | LV1802B | Cimentaciones de equipos y pedestales del fabricante · revisión recibida 04/09/2026 | 2718/25CB, 2718/E3A8, 1FEC2 | -2 | -1.4 | 13.6242 | Cotas relativas del dibujo. La equivalencia con un datum absoluto está pendiente. | Z del modelo = cota relativa + 1,10 m. Correspondencia provisional con 286,10 m; no es cota de obra confirmada. | Sección y contornos del fabricante; incidencias conservadas | 4.038 | 3.374 | Planta: −2,400 m. Sección 8–8: fondo −2,000 m, coronación de losa −1,400 m. Se adopta sección; pendiente de aclaración.
Cimentación del vaporizador LV1802B · pedestal DZ8 1 | Parcela industrial Jinhong | Cimentación industrial | Cimentaciones de equipos y pedestales del fabricante · revisión recibida 04/09/2026 | 1.00058 | 0.915128 | 1.865 | 7.781 | 1.3428 | process_plant | Zona de separación de aire | {"name":"Hormigón armado · clase pendiente de confirmar","status":"Clase no confirmada en la hoja de equipo","source":"Geometría de cimentación del fabricante; no se extrapola HA-30 de la nota de pedestales."} | {"documented":[{"label":"Extensión local X","value":0.9,"unit":"m","source":"2718/25CB, 2718/E3A8, 1FEC2","status":"derivada del contorno CAD"},{"label":"Extensión local Y","value":0.8,"unit":"m","source":"2718/25CB, 2718/E3A8, 1FEC2","status":"derivada del contorno CAD"},{"label":"Cota inferior relativa adoptada","value":-1.4,"unit":"m","source":"8–8","status":"interpretación con conflicto conservado"},{"label":"Cota superior relativa adoptada","value":0.465,"unit":"m","source":"8–8","status":"documentada / separación por material"}],"geometry":[{"label":"Extensión de la malla en X","value":1.0005760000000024,"unit":"m","source":"Geometría releída del IFC; datum absoluto de proceso provisional","status":"derivado"},{"label":"Extensión de la malla en Y","value":0.9151279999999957,"unit":"m","source":"Geometría releída del IFC; datum absoluto de proceso provisional","status":"derivado"},{"label":"Extensión de la malla en Z","value":1.865,"unit":"m","source":"Geometría releída del IFC; datum absoluto de proceso provisional","status":"derivado"},{"label":"Cota inferior de visualización","value":284.7,"unit":"m","source":"Geometría releída del IFC; datum absoluto de proceso provisional","status":"derivado"},{"label":"Cota superior de visualización","value":286.565,"unit":"m","source":"Geometría releída del IFC; datum absoluto de proceso provisional","status":"derivado"}]} | {"documentId":"LHD2609-JG00100-20260904","title":"Cimentaciones de equipos y pedestales del fabricante · revisión recibida 04/09/2026","date":"2026-09-04","sheet":"8–8","fileName":"LHD2609-JG00100_20260904.dwg","revisionCaveat":"Fecha de revisión tomada del nombre recibido; cajetines internos mantienen 02/07/2026 y algunos textos de plantilla.","sourceFileSha256":"b42eb027b7bc0b14c38d1d13514f4899b58a732aa8d0ba2ccf10fa2fc3192890"} | provisional | ["Planta: −2,400 m. Sección 8–8: fondo −2,000 m, coronación de losa −1,400 m. Se adopta sección; pendiente de aclaración."] | {"Cota inferior relativa (m)":-1.4,"Cota superior relativa (m)":0.465,"Cero absoluto de visualización (m)":286.1,"Estado del cero absoluto":"Provisional","Criterio":"Las cotas relativas proceden del dibujo; la equivalencia absoluta no está confirmada."} | {"boundingBoxM":{"min":[40.091068,37.218549,-0.3],"max":[41.091644,38.133677,1.565]},"extentsM":[1.000576,0.915128,1.865],"meshSurfaceM2":7.781,"meshVolumeM3":1.3428,"closedSolid":true,"basis":"Magnitudes de las mallas representadas, no cantidades certificadas de obra, compra o fabricación. Las partes pueden compartir superficies; no se suman como un despiece de materiales."} | {"profileId":"concrete_reinforced","name":"Hormigón armado · gris natural","materialName":"Hormigón armado · clase pendiente de confirmar","physicalMaterialStatus":"Clase no confirmada en la hoja de equipo","physicalMaterialSource":"Geometría de cimentación del fabricante; no se extrapola HA-30 de la nota de pedestales.","appearanceStatus":"criterio_visual","appearanceBasis":"Interpretación visual del material documental; el acabado, tono y parámetros PBR no son una especificación contractual.","note":"La apariencia gráfica no modifica ni confirma la especificación física del material."} | {"elementId":"found_0904_e186e53af6b768","ifcGuid":"0Sm0k4GLXIPgTeEKOlzT4O","ifcClass":"IfcFooting","buildingId":"process_plant","buildingName":"Zona de separación de aire","sourceDocumentId":"LHD2609-JG00100-20260904","sourceRepresentationKind":"foundation"} | {"layerId":"foundations","layerName":"Cimentaciones","role":"Cimentación industrial","basis":"Clasificación por función del elemento; no modifica las especificaciones documentales."} | {"profileId":"concrete_reinforced","name":"Hormigón armado · gris natural","status":"criterio_visual","basis":"Interpretación visual del material documental; el acabado, tono y parámetros PBR no son una especificación contractual.","physicalMaterialUnchanged":true} | 1.3428 | Hormigón armado · clase pendiente de confirmar | Hormigón armado · gris natural | found_0904_e186e53af6b768 | Geometría de cimentación del fabricante; no se extrapola HA-30 de la nota de pedestales. | Clase no confirmada en la hoja de equipo | concrete_reinforced | [0.666667,0.662745,0.619608] | 0.96 | Zona de separación de aire; BIM · Cimentaciones | 1.00058 | 0.915128 | 1.865 | 284.7 | 286.565 | F-LV1802B | ["LV1802B"] | [] | 8–8 | ["2718/25CB","2718/E3A8","1FEC2"] | F-LV1802B/Cimentación del vaporizador LV1802B · pedestal DZ8 1 | foundation | Geometría de fabricante; implantación absoluta provisional | LV1802B | Cimentaciones de equipos y pedestales del fabricante · revisión recibida 04/09/2026 | 2718/25CB, 2718/E3A8, 1FEC2 | -1.4 | 0.465 | 0.72 | Cotas relativas del dibujo. La equivalencia con un datum absoluto está pendiente. | Z del modelo = cota relativa + 1,10 m. Correspondencia provisional con 286,10 m; no es cota de obra confirmada. | Sección y contornos del fabricante; incidencias conservadas | 0.9 | 0.8 | Planta: −2,400 m. Sección 8–8: fondo −2,000 m, coronación de losa −1,400 m. Se adopta sección; pendiente de aclaración.
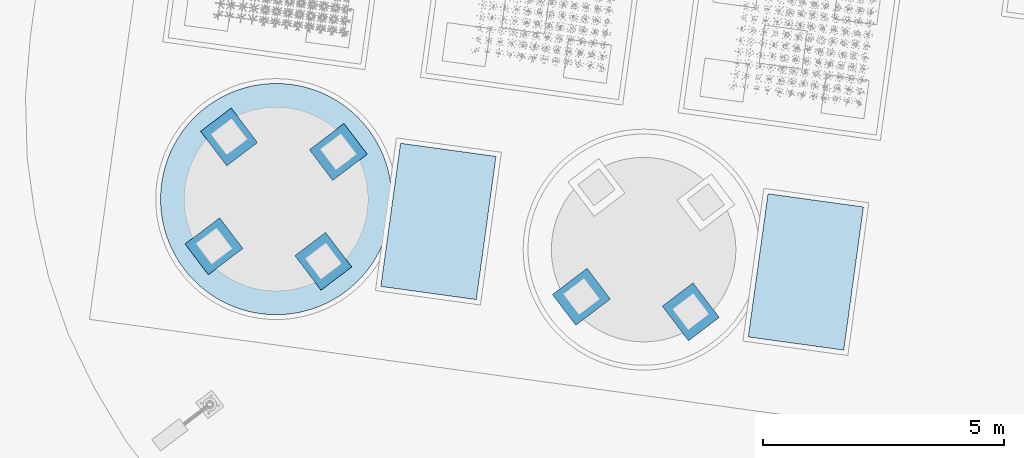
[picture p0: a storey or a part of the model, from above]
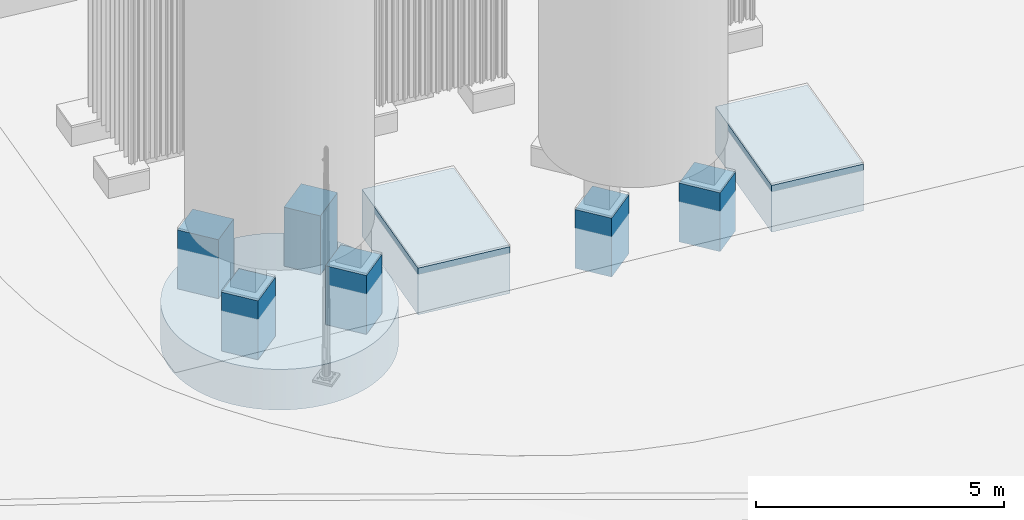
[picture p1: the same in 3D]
Properties of the parts of a building model (IFC4), part 69 of 134

# IfcFooting (214)
Name | In | Description = category = Categoria = Funcion | Document | ExtensionX (m) | ExtensionY (m) | ExtensionZ (m) | SuperficieDeLaMalla (m2) | VolumenGeometrico (m3) | buildingId | buildingName | material | dimensions | JH_InformacionBIM, source = DocumentoFuente | JH_InformacionBIM, status = EstadoDeInformacion | issues = IncidenciasPendientes | positioning = PosicionYEstado | geometryMetrics | materialAppearance | visualizationIdentity | classification | appearance | Volumen geométrico (m³) | JH_Trazabilidad, Material = name | Acabado de visualización = Acabado | Identificador | JH_EvidenciaDeMaterial, source | JH_EvidenciaDeMaterial, status | Perfil | ColorRGB | Rugosidad | Group | Extensión de la malla en X (m) | Extensión de la malla en Y (m) | Extensión de la malla en Z (m) = Espesor o altura real de sección (m) | Cota inferior de visualización (m) | Cota superior de visualización (m) | assemblyId = Conjunto de cimentación | equipmentIds | supportPositionIds | sectionRef = Sección de referencia | sourceCadHandles | stableElementKey | representationKind | geometryStatus | Equipos asociados | Documento de origen | Identificadores CAD de referencia | Cota inferior relativa (m) = Cota inferior relativa adoptada (m) | Cota superior relativa (m) = Cota superior relativa adoptada (m) | Área de planta (m²) | Referencia vertical | Implantación para visualización | Estado de la geometría | Extensión local X (m) | Extensión local Y (m) | Incidencias de origen
Cimentación del vaporizador LV1802B · pedestal DZ8 2 | Parcela industrial Jinhong | Cimentación industrial | Cimentaciones de equipos y pedestales del fabricante · revisión recibida 04/09/2026 | 1.00058 | 0.915128 | 1.865 | 7.781 | 1.3428 | process_plant | Zona de separación de aire | {"name":"Hormigón armado · clase pendiente de confirmar","status":"Clase no confirmada en la hoja de equipo","source":"Geometría de cimentación del fabricante; no se extrapola HA-30 de la nota de pedestales."} | {"documented":[{"label":"Extensión local X","value":0.9,"unit":"m","source":"2718/25CB, 2718/E3A8, 1FEC2","status":"derivada del contorno CAD"},{"label":"Extensión local Y","value":0.8,"unit":"m","source":"2718/25CB, 2718/E3A8, 1FEC2","status":"derivada del contorno CAD"},{"label":"Cota inferior relativa adoptada","value":-1.4,"unit":"m","source":"8–8","status":"interpretación con conflicto conservado"},{"label":"Cota superior relativa adoptada","value":0.465,"unit":"m","source":"8–8","status":"documentada / separación por material"}],"geometry":[{"label":"Extensión de la malla en X","value":1.0005760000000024,"unit":"m","source":"Geometría releída del IFC; datum absoluto de proceso provisional","status":"derivado"},{"label":"Extensión de la malla en Y","value":0.9151279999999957,"unit":"m","source":"Geometría releída del IFC; datum absoluto de proceso provisional","status":"derivado"},{"label":"Extensión de la malla en Z","value":1.865,"unit":"m","source":"Geometría releída del IFC; datum absoluto de proceso provisional","status":"derivado"},{"label":"Cota inferior de visualización","value":284.7,"unit":"m","source":"Geometría releída del IFC; datum absoluto de proceso provisional","status":"derivado"},{"label":"Cota superior de visualización","value":286.565,"unit":"m","source":"Geometría releída del IFC; datum absoluto de proceso provisional","status":"derivado"}]} | {"documentId":"LHD2609-JG00100-20260904","title":"Cimentaciones de equipos y pedestales del fabricante · revisión recibida 04/09/2026","date":"2026-09-04","sheet":"8–8","fileName":"LHD2609-JG00100_20260904.dwg","revisionCaveat":"Fecha de revisión tomada del nombre recibido; cajetines internos mantienen 02/07/2026 y algunos textos de plantilla.","sourceFileSha256":"b42eb027b7bc0b14c38d1d13514f4899b58a732aa8d0ba2ccf10fa2fc3192890"} | provisional | ["Planta: −2,400 m. Sección 8–8: fondo −2,000 m, coronación de losa −1,400 m. Se adopta sección; pendiente de aclaración."] | {"Cota inferior relativa (m)":-1.4,"Cota superior relativa (m)":0.465,"Cero absoluto de visualización (m)":286.1,"Estado del cero absoluto":"Provisional","Criterio":"Las cotas relativas proceden del dibujo; la equivalencia absoluta no está confirmada."} | {"boundingBoxM":{"min":[42.605416,36.872863,-0.3],"max":[43.605992,37.787991,1.565]},"extentsM":[1.000576,0.915128,1.865],"meshSurfaceM2":7.780998,"meshVolumeM3":1.342799,"closedSolid":true,"basis":"Magnitudes de las mallas representadas, no cantidades certificadas de obra, compra o fabricación. Las partes pueden compartir superficies; no se suman como un despiece de materiales."} | {"profileId":"concrete_reinforced","name":"Hormigón armado · gris natural","materialName":"Hormigón armado · clase pendiente de confirmar","physicalMaterialStatus":"Clase no confirmada en la hoja de equipo","physicalMaterialSource":"Geometría de cimentación del fabricante; no se extrapola HA-30 de la nota de pedestales.","appearanceStatus":"criterio_visual","appearanceBasis":"Interpretación visual del material documental; el acabado, tono y parámetros PBR no son una especificación contractual.","note":"La apariencia gráfica no modifica ni confirma la especificación física del material."} | {"elementId":"found_0904_6def6a5a7fdab6","ifcGuid":"2AgwaQ4pPNVOZG85k8VdsG","ifcClass":"IfcFooting","buildingId":"process_plant","buildingName":"Zona de separación de aire","sourceDocumentId":"LHD2609-JG00100-20260904","sourceRepresentationKind":"foundation"} | {"layerId":"foundations","layerName":"Cimentaciones","role":"Cimentación industrial","basis":"Clasificación por función del elemento; no modifica las especificaciones documentales."} | {"profileId":"concrete_reinforced","name":"Hormigón armado · gris natural","status":"criterio_visual","basis":"Interpretación visual del material documental; el acabado, tono y parámetros PBR no son una especificación contractual.","physicalMaterialUnchanged":true} | 1.3428 | Hormigón armado · clase pendiente de confirmar | Hormigón armado · gris natural | found_0904_6def6a5a7fdab6 | Geometría de cimentación del fabricante; no se extrapola HA-30 de la nota de pedestales. | Clase no confirmada en la hoja de equipo | concrete_reinforced | [0.666667,0.662745,0.619608] | 0.96 | Zona de separación de aire; BIM · Cimentaciones | 1.00058 | 0.915128 | 1.865 | 284.7 | 286.565 | F-LV1802B | ["LV1802B"] | [] | 8–8 | ["2718/25CB","2718/E3A8","1FEC2"] | F-LV1802B/Cimentación del vaporizador LV1802B · pedestal DZ8 2 | foundation | Geometría de fabricante; implantación absoluta provisional | LV1802B | Cimentaciones de equipos y pedestales del fabricante · revisión recibida 04/09/2026 | 2718/25CB, 2718/E3A8, 1FEC2 | -1.4 | 0.465 | 0.72 | Cotas relativas del dibujo. La equivalencia con un datum absoluto está pendiente. | Z del modelo = cota relativa + 1,10 m. Correspondencia provisional con 286,10 m; no es cota de obra confirmada. | Sección y contornos del fabricante; incidencias conservadas | 0.9 | 0.8 | Planta: −2,400 m. Sección 8–8: fondo −2,000 m, coronación de losa −1,400 m. Se adopta sección; pendiente de aclaración.
Cimentación del vaporizador LV1802B · pedestal DZ8 3 | Parcela industrial Jinhong | Cimentación industrial | Cimentaciones de equipos y pedestales del fabricante · revisión recibida 04/09/2026 | 1.00058 | 0.915128 | 1.865 | 7.781 | 1.3428 | process_plant | Zona de separación de aire | {"name":"Hormigón armado · clase pendiente de confirmar","status":"Clase no confirmada en la hoja de equipo","source":"Geometría de cimentación del fabricante; no se extrapola HA-30 de la nota de pedestales."} | {"documented":[{"label":"Extensión local X","value":0.9,"unit":"m","source":"2718/25CB, 2718/E3A8, 1FEC2","status":"derivada del contorno CAD"},{"label":"Extensión local Y","value":0.8,"unit":"m","source":"2718/25CB, 2718/E3A8, 1FEC2","status":"derivada del contorno CAD"},{"label":"Cota inferior relativa adoptada","value":-1.4,"unit":"m","source":"8–8","status":"interpretación con conflicto conservado"},{"label":"Cota superior relativa adoptada","value":0.465,"unit":"m","source":"8–8","status":"documentada / separación por material"}],"geometry":[{"label":"Extensión de la malla en X","value":1.0005760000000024,"unit":"m","source":"Geometría releída del IFC; datum absoluto de proceso provisional","status":"derivado"},{"label":"Extensión de la malla en Y","value":0.9151279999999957,"unit":"m","source":"Geometría releída del IFC; datum absoluto de proceso provisional","status":"derivado"},{"label":"Extensión de la malla en Z","value":1.865,"unit":"m","source":"Geometría releída del IFC; datum absoluto de proceso provisional","status":"derivado"},{"label":"Cota inferior de visualización","value":284.7,"unit":"m","source":"Geometría releída del IFC; datum absoluto de proceso provisional","status":"derivado"},{"label":"Cota superior de visualización","value":286.565,"unit":"m","source":"Geometría releída del IFC; datum absoluto de proceso provisional","status":"derivado"}]} | {"documentId":"LHD2609-JG00100-20260904","title":"Cimentaciones de equipos y pedestales del fabricante · revisión recibida 04/09/2026","date":"2026-09-04","sheet":"8–8","fileName":"LHD2609-JG00100_20260904.dwg","revisionCaveat":"Fecha de revisión tomada del nombre recibido; cajetines internos mantienen 02/07/2026 y algunos textos de plantilla.","sourceFileSha256":"b42eb027b7bc0b14c38d1d13514f4899b58a732aa8d0ba2ccf10fa2fc3192890"} | provisional | ["Planta: −2,400 m. Sección 8–8: fondo −2,000 m, coronación de losa −1,400 m. Se adopta sección; pendiente de aclaración."] | {"Cota inferior relativa (m)":-1.4,"Cota superior relativa (m)":0.465,"Cero absoluto de visualización (m)":286.1,"Estado del cero absoluto":"Provisional","Criterio":"Las cotas relativas proceden del dibujo; la equivalencia absoluta no está confirmada."} | {"boundingBoxM":{"min":[42.336549,34.917259,-0.3],"max":[43.337125,35.832387,1.565]},"extentsM":[1.000576,0.915128,1.865],"meshSurfaceM2":7.781,"meshVolumeM3":1.3428,"closedSolid":true,"basis":"Magnitudes de las mallas representadas, no cantidades certificadas de obra, compra o fabricación. Las partes pueden compartir superficies; no se suman como un despiece de materiales."} | {"profileId":"concrete_reinforced","name":"Hormigón armado · gris natural","materialName":"Hormigón armado · clase pendiente de confirmar","physicalMaterialStatus":"Clase no confirmada en la hoja de equipo","physicalMaterialSource":"Geometría de cimentación del fabricante; no se extrapola HA-30 de la nota de pedestales.","appearanceStatus":"criterio_visual","appearanceBasis":"Interpretación visual del material documental; el acabado, tono y parámetros PBR no son una especificación contractual.","note":"La apariencia gráfica no modifica ni confirma la especificación física del material."} | {"elementId":"found_0904_2c4c84af4d4d91","ifcGuid":"3D91byMYrS8hWpB4nsR03W","ifcClass":"IfcFooting","buildingId":"process_plant","buildingName":"Zona de separación de aire","sourceDocumentId":"LHD2609-JG00100-20260904","sourceRepresentationKind":"foundation"} | {"layerId":"foundations","layerName":"Cimentaciones","role":"Cimentación industrial","basis":"Clasificación por función del elemento; no modifica las especificaciones documentales."} | {"profileId":"concrete_reinforced","name":"Hormigón armado · gris natural","status":"criterio_visual","basis":"Interpretación visual del material documental; el acabado, tono y parámetros PBR no son una especificación contractual.","physicalMaterialUnchanged":true} | 1.3428 | Hormigón armado · clase pendiente de confirmar | Hormigón armado · gris natural | found_0904_2c4c84af4d4d91 | Geometría de cimentación del fabricante; no se extrapola HA-30 de la nota de pedestales. | Clase no confirmada en la hoja de equipo | concrete_reinforced | [0.666667,0.662745,0.619608] | 0.96 | Zona de separación de aire; BIM · Cimentaciones | 1.00058 | 0.915128 | 1.865 | 284.7 | 286.565 | F-LV1802B | ["LV1802B"] | [] | 8–8 | ["2718/25CB","2718/E3A8","1FEC2"] | F-LV1802B/Cimentación del vaporizador LV1802B · pedestal DZ8 3 | foundation | Geometría de fabricante; implantación absoluta provisional | LV1802B | Cimentaciones de equipos y pedestales del fabricante · revisión recibida 04/09/2026 | 2718/25CB, 2718/E3A8, 1FEC2 | -1.4 | 0.465 | 0.72 | Cotas relativas del dibujo. La equivalencia con un datum absoluto está pendiente. | Z del modelo = cota relativa + 1,10 m. Correspondencia provisional con 286,10 m; no es cota de obra confirmada. | Sección y contornos del fabricante; incidencias conservadas | 0.9 | 0.8 | Planta: −2,400 m. Sección 8–8: fondo −2,000 m, coronación de losa −1,400 m. Se adopta sección; pendiente de aclaración.
Cimentación del vaporizador LV1802B · pedestal DZ8 4 | Parcela industrial Jinhong | Cimentación industrial | Cimentaciones de equipos y pedestales del fabricante · revisión recibida 04/09/2026 | 1.00058 | 0.915128 | 1.865 | 7.781 | 1.3428 | process_plant | Zona de separación de aire | {"name":"Hormigón armado · clase pendiente de confirmar","status":"Clase no confirmada en la hoja de equipo","source":"Geometría de cimentación del fabricante; no se extrapola HA-30 de la nota de pedestales."} | {"documented":[{"label":"Extensión local X","value":0.9,"unit":"m","source":"2718/25CB, 2718/E3A8, 1FEC2","status":"derivada del contorno CAD"},{"label":"Extensión local Y","value":0.8,"unit":"m","source":"2718/25CB, 2718/E3A8, 1FEC2","status":"derivada del contorno CAD"},{"label":"Cota inferior relativa adoptada","value":-1.4,"unit":"m","source":"8–8","status":"interpretación con conflicto conservado"},{"label":"Cota superior relativa adoptada","value":0.465,"unit":"m","source":"8–8","status":"documentada / separación por material"}],"geometry":[{"label":"Extensión de la malla en X","value":1.0005760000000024,"unit":"m","source":"Geometría releída del IFC; datum absoluto de proceso provisional","status":"derivado"},{"label":"Extensión de la malla en Y","value":0.9151279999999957,"unit":"m","source":"Geometría releída del IFC; datum absoluto de proceso provisional","status":"derivado"},{"label":"Extensión de la malla en Z","value":1.865,"unit":"m","source":"Geometría releída del IFC; datum absoluto de proceso provisional","status":"derivado"},{"label":"Cota inferior de visualización","value":284.7,"unit":"m","source":"Geometría releída del IFC; datum absoluto de proceso provisional","status":"derivado"},{"label":"Cota superior de visualización","value":286.565,"unit":"m","source":"Geometría releída del IFC; datum absoluto de proceso provisional","status":"derivado"}]} | {"documentId":"LHD2609-JG00100-20260904","title":"Cimentaciones de equipos y pedestales del fabricante · revisión recibida 04/09/2026","date":"2026-09-04","sheet":"8–8","fileName":"LHD2609-JG00100_20260904.dwg","revisionCaveat":"Fecha de revisión tomada del nombre recibido; cajetines internos mantienen 02/07/2026 y algunos textos de plantilla.","sourceFileSha256":"b42eb027b7bc0b14c38d1d13514f4899b58a732aa8d0ba2ccf10fa2fc3192890"} | provisional | ["Planta: −2,400 m. Sección 8–8: fondo −2,000 m, coronación de losa −1,400 m. Se adopta sección; pendiente de aclaración."] | {"Cota inferior relativa (m)":-1.4,"Cota superior relativa (m)":0.465,"Cero absoluto de visualización (m)":286.1,"Estado del cero absoluto":"Provisional","Criterio":"Las cotas relativas proceden del dibujo; la equivalencia absoluta no está confirmada."} | {"boundingBoxM":{"min":[39.822201,35.262945,-0.3],"max":[40.822777,36.178073,1.565]},"extentsM":[1.000576,0.915128,1.865],"meshSurfaceM2":7.781,"meshVolumeM3":1.3428,"closedSolid":true,"basis":"Magnitudes de las mallas representadas, no cantidades certificadas de obra, compra o fabricación. Las partes pueden compartir superficies; no se suman como un despiece de materiales."} | {"profileId":"concrete_reinforced","name":"Hormigón armado · gris natural","materialName":"Hormigón armado · clase pendiente de confirmar","physicalMaterialStatus":"Clase no confirmada en la hoja de equipo","physicalMaterialSource":"Geometría de cimentación del fabricante; no se extrapola HA-30 de la nota de pedestales.","appearanceStatus":"criterio_visual","appearanceBasis":"Interpretación visual del material documental; el acabado, tono y parámetros PBR no son una especificación contractual.","note":"La apariencia gráfica no modifica ni confirma la especificación física del material."} | {"elementId":"found_0904_feeaf076bc98f8","ifcGuid":"2MWPowGP9QMeb2csrwuiQl","ifcClass":"IfcFooting","buildingId":"process_plant","buildingName":"Zona de separación de aire","sourceDocumentId":"LHD2609-JG00100-20260904","sourceRepresentationKind":"foundation"} | {"layerId":"foundations","layerName":"Cimentaciones","role":"Cimentación industrial","basis":"Clasificación por función del elemento; no modifica las especificaciones documentales."} | {"profileId":"concrete_reinforced","name":"Hormigón armado · gris natural","status":"criterio_visual","basis":"Interpretación visual del material documental; el acabado, tono y parámetros PBR no son una especificación contractual.","physicalMaterialUnchanged":true} | 1.3428 | Hormigón armado · clase pendiente de confirmar | Hormigón armado · gris natural | found_0904_feeaf076bc98f8 | Geometría de cimentación del fabricante; no se extrapola HA-30 de la nota de pedestales. | Clase no confirmada en la hoja de equipo | concrete_reinforced | [0.666667,0.662745,0.619608] | 0.96 | Zona de separación de aire; BIM · Cimentaciones | 1.00058 | 0.915128 | 1.865 | 284.7 | 286.565 | F-LV1802B | ["LV1802B"] | [] | 8–8 | ["2718/25CB","2718/E3A8","1FEC2"] | F-LV1802B/Cimentación del vaporizador LV1802B · pedestal DZ8 4 | foundation | Geometría de fabricante; implantación absoluta provisional | LV1802B | Cimentaciones de equipos y pedestales del fabricante · revisión recibida 04/09/2026 | 2718/25CB, 2718/E3A8, 1FEC2 | -1.4 | 0.465 | 0.72 | Cotas relativas del dibujo. La equivalencia con un datum absoluto está pendiente. | Z del modelo = cota relativa + 1,10 m. Correspondencia provisional con 286,10 m; no es cota de obra confirmada. | Sección y contornos del fabricante; incidencias conservadas | 0.9 | 0.8 | Planta: −2,400 m. Sección 8–8: fondo −2,000 m, coronación de losa −1,400 m. Se adopta sección; pendiente de aclaración.
Cimentación del vaporizador LV1802B · pedestal DZ8 5 | Parcela industrial Jinhong | Cimentación industrial | Cimentaciones de equipos y pedestales del fabricante · revisión recibida 04/09/2026 | 1.00058 | 0.915128 | 1.865 | 7.781 | 1.3428 | process_plant | Zona de separación de aire | {"name":"Hormigón armado · clase pendiente de confirmar","status":"Clase no confirmada en la hoja de equipo","source":"Geometría de cimentación del fabricante; no se extrapola HA-30 de la nota de pedestales."} | {"documented":[{"label":"Extensión local X","value":0.9,"unit":"m","source":"2718/25CB, 2718/E3A8, 1FEC2","status":"derivada del contorno CAD"},{"label":"Extensión local Y","value":0.8,"unit":"m","source":"2718/25CB, 2718/E3A8, 1FEC2","status":"derivada del contorno CAD"},{"label":"Cota inferior relativa adoptada","value":-1.4,"unit":"m","source":"8–8","status":"interpretación con conflicto conservado"},{"label":"Cota superior relativa adoptada","value":0.465,"unit":"m","source":"8–8","status":"documentada / separación por material"}],"geometry":[{"label":"Extensión de la malla en X","value":1.0005760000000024,"unit":"m","source":"Geometría releída del IFC; datum absoluto de proceso provisional","status":"derivado"},{"label":"Extensión de la malla en Y","value":0.9151280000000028,"unit":"m","source":"Geometría releída del IFC; datum absoluto de proceso provisional","status":"derivado"},{"label":"Extensión de la malla en Z","value":1.865,"unit":"m","source":"Geometría releída del IFC; datum absoluto de proceso provisional","status":"derivado"},{"label":"Cota inferior de visualización","value":284.7,"unit":"m","source":"Geometría releída del IFC; datum absoluto de proceso provisional","status":"derivado"},{"label":"Cota superior de visualización","value":286.565,"unit":"m","source":"Geometría releída del IFC; datum absoluto de proceso provisional","status":"derivado"}]} | {"documentId":"LHD2609-JG00100-20260904","title":"Cimentaciones de equipos y pedestales del fabricante · revisión recibida 04/09/2026","date":"2026-09-04","sheet":"8–8","fileName":"LHD2609-JG00100_20260904.dwg","revisionCaveat":"Fecha de revisión tomada del nombre recibido; cajetines internos mantienen 02/07/2026 y algunos textos de plantilla.","sourceFileSha256":"b42eb027b7bc0b14c38d1d13514f4899b58a732aa8d0ba2ccf10fa2fc3192890"} | provisional | ["Planta: −2,400 m. Sección 8–8: fondo −2,000 m, coronación de losa −1,400 m. Se adopta sección; pendiente de aclaración."] | {"Cota inferior relativa (m)":-1.4,"Cota superior relativa (m)":0.465,"Cero absoluto de visualización (m)":286.1,"Estado del cero absoluto":"Provisional","Criterio":"Las cotas relativas proceden del dibujo; la equivalencia absoluta no está confirmada."} | {"boundingBoxM":{"min":[41.054918,35.947423,-0.3],"max":[42.055494,36.862551,1.565]},"extentsM":[1.000576,0.915128,1.865],"meshSurfaceM2":7.780998,"meshVolumeM3":1.342799,"closedSolid":true,"basis":"Magnitudes de las mallas representadas, no cantidades certificadas de obra, compra o fabricación. Las partes pueden compartir superficies; no se suman como un despiece de materiales."} | {"profileId":"concrete_reinforced","name":"Hormigón armado · gris natural","materialName":"Hormigón armado · clase pendiente de confirmar","physicalMaterialStatus":"Clase no confirmada en la hoja de equipo","physicalMaterialSource":"Geometría de cimentación del fabricante; no se extrapola HA-30 de la nota de pedestales.","appearanceStatus":"criterio_visual","appearanceBasis":"Interpretación visual del material documental; el acabado, tono y parámetros PBR no son una especificación contractual.","note":"La apariencia gráfica no modifica ni confirma la especificación física del material."} | {"elementId":"found_0904_5af42dcdd2d975","ifcGuid":"2VCiEHGgDL4O8VnOONep8f","ifcClass":"IfcFooting","buildingId":"process_plant","buildingName":"Zona de separación de aire","sourceDocumentId":"LHD2609-JG00100-20260904","sourceRepresentationKind":"foundation"} | {"layerId":"foundations","layerName":"Cimentaciones","role":"Cimentación industrial","basis":"Clasificación por función del elemento; no modifica las especificaciones documentales."} | {"profileId":"concrete_reinforced","name":"Hormigón armado · gris natural","status":"criterio_visual","basis":"Interpretación visual del material documental; el acabado, tono y parámetros PBR no son una especificación contractual.","physicalMaterialUnchanged":true} | 1.3428 | Hormigón armado · clase pendiente de confirmar | Hormigón armado · gris natural | found_0904_5af42dcdd2d975 | Geometría de cimentación del fabricante; no se extrapola HA-30 de la nota de pedestales. | Clase no confirmada en la hoja de equipo | concrete_reinforced | [0.666667,0.662745,0.619608] | 0.96 | Zona de separación de aire; BIM · Cimentaciones | 1.00058 | 0.915128 | 1.865 | 284.7 | 286.565 | F-LV1802B | ["LV1802B"] | [] | 8–8 | ["2718/25CB","2718/E3A8","1FEC2"] | F-LV1802B/Cimentación del vaporizador LV1802B · pedestal DZ8 5 | foundation | Geometría de fabricante; implantación absoluta provisional | LV1802B | Cimentaciones de equipos y pedestales del fabricante · revisión recibida 04/09/2026 | 2718/25CB, 2718/E3A8, 1FEC2 | -1.4 | 0.465 | 0.72 | Cotas relativas del dibujo. La equivalencia con un datum absoluto está pendiente. | Z del modelo = cota relativa + 1,10 m. Correspondencia provisional con 286,10 m; no es cota de obra confirmada. | Sección y contornos del fabricante; incidencias conservadas | 0.9 | 0.8 | Planta: −2,400 m. Sección 8–8: fondo −2,000 m, coronación de losa −1,400 m. Se adopta sección; pendiente de aclaración.
Cimentación del vaporizador LV1802C · cuerpo de hormigón | Parcela industrial Jinhong | Cimentación industrial | Cimentaciones de equipos y pedestales del fabricante · revisión recibida 04/09/2026 | 4.45992 | 3.89255 | 0.6 | 36.1428 | 8.17453 | process_plant | Zona de separación de aire | {"name":"Hormigón armado · clase pendiente de confirmar","status":"Clase no confirmada en la hoja de equipo","source":"Geometría de cimentación del fabricante; no se extrapola HA-30 de la nota de pedestales."} | {"documented":[{"label":"Extensión local X","value":4.038,"unit":"m","source":"2719/25CB, 2719/E3A8, 1FEC2","status":"derivada del contorno CAD"},{"label":"Extensión local Y","value":3.374,"unit":"m","source":"2719/25CB, 2719/E3A8, 1FEC2","status":"derivada del contorno CAD"},{"label":"Cota inferior relativa adoptada","value":-2,"unit":"m","source":"8–8","status":"interpretación con conflicto conservado"},{"label":"Cota superior relativa adoptada","value":-1.4,"unit":"m","source":"8–8","status":"documentada / separación por material"}],"geometry":[{"label":"Extensión de la malla en X","value":4.459921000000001,"unit":"m","source":"Geometría releída del IFC; datum absoluto de proceso provisional","status":"derivado"},{"label":"Extensión de la malla en Y","value":3.892547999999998,"unit":"m","source":"Geometría releída del IFC; datum absoluto de proceso provisional","status":"derivado"},{"label":"Extensión de la malla en Z","value":0.6000000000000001,"unit":"m","source":"Geometría releída del IFC; datum absoluto de proceso provisional","status":"derivado"},{"label":"Cota inferior de visualización","value":284.1,"unit":"m","source":"Geometría releída del IFC; datum absoluto de proceso provisional","status":"derivado"},{"label":"Cota superior de visualización","value":284.7,"unit":"m","source":"Geometría releída del IFC; datum absoluto de proceso provisional","status":"derivado"}]} | {"documentId":"LHD2609-JG00100-20260904","title":"Cimentaciones de equipos y pedestales del fabricante · revisión recibida 04/09/2026","date":"2026-09-04","sheet":"8–8","fileName":"LHD2609-JG00100_20260904.dwg","revisionCaveat":"Fecha de revisión tomada del nombre recibido; cajetines internos mantienen 02/07/2026 y algunos textos de plantilla.","sourceFileSha256":"b42eb027b7bc0b14c38d1d13514f4899b58a732aa8d0ba2ccf10fa2fc3192890"} | provisional | ["Planta: −2,400 m. Sección 8–8: fondo −2,000 m, coronación de losa −1,400 m. Se adopta sección; pendiente de aclaración."] | {"Cota inferior relativa (m)":-2,"Cota superior relativa (m)":-1.4,"Cero absoluto de visualización (m)":286.1,"Estado del cero absoluto":"Provisional","Criterio":"Las cotas relativas proceden del dibujo; la equivalencia absoluta no está confirmada."} | {"boundingBoxM":{"min":[44.833812,33.843693,-0.9],"max":[49.293733,37.736241,-0.3]},"extentsM":[4.459921,3.892548,0.6],"meshSurfaceM2":36.142821,"meshVolumeM3":8.174527,"closedSolid":true,"basis":"Magnitudes de las mallas representadas, no cantidades certificadas de obra, compra o fabricación. Las partes pueden compartir superficies; no se suman como un despiece de materiales."} | {"profileId":"concrete_reinforced","name":"Hormigón armado · gris natural","materialName":"Hormigón armado · clase pendiente de confirmar","physicalMaterialStatus":"Clase no confirmada en la hoja de equipo","physicalMaterialSource":"Geometría de cimentación del fabricante; no se extrapola HA-30 de la nota de pedestales.","appearanceStatus":"criterio_visual","appearanceBasis":"Interpretación visual del material documental; el acabado, tono y parámetros PBR no son una especificación contractual.","note":"La apariencia gráfica no modifica ni confirma la especificación física del material."} | {"elementId":"found_0904_4939b606bb2942","ifcGuid":"1YGcCN1iHPPRNBs$GM4y1t","ifcClass":"IfcFooting","buildingId":"process_plant","buildingName":"Zona de separación de aire","sourceDocumentId":"LHD2609-JG00100-20260904","sourceRepresentationKind":"foundation"} | {"layerId":"foundations","layerName":"Cimentaciones","role":"Cimentación industrial","basis":"Clasificación por función del elemento; no modifica las especificaciones documentales."} | {"profileId":"concrete_reinforced","name":"Hormigón armado · gris natural","status":"criterio_visual","basis":"Interpretación visual del material documental; el acabado, tono y parámetros PBR no son una especificación contractual.","physicalMaterialUnchanged":true} | 8.17453 | Hormigón armado · clase pendiente de confirmar | Hormigón armado · gris natural | found_0904_4939b606bb2942 | Geometría de cimentación del fabricante; no se extrapola HA-30 de la nota de pedestales. | Clase no confirmada en la hoja de equipo | concrete_reinforced | [0.666667,0.662745,0.619608] | 0.96 | Zona de separación de aire; BIM · Cimentaciones | 4.45992 | 3.89255 | 0.6 | 284.1 | 284.7 | F-LV1802C | ["LV1802C"] | [] | 8–8 | ["2719/25CB","2719/E3A8","1FEC2"] | F-LV1802C/Cimentación del vaporizador LV1802C · cuerpo de hormigón | foundation | Geometría de fabricante; implantación absoluta provisional | LV1802C | Cimentaciones de equipos y pedestales del fabricante · revisión recibida 04/09/2026 | 2719/25CB, 2719/E3A8, 1FEC2 | -2 | -1.4 | 13.6242 | Cotas relativas del dibujo. La equivalencia con un datum absoluto está pendiente. | Z del modelo = cota relativa + 1,10 m. Correspondencia provisional con 286,10 m; no es cota de obra confirmada. | Sección y contornos del fabricante; incidencias conservadas | 4.038 | 3.374 | Planta: −2,400 m. Sección 8–8: fondo −2,000 m, coronación de losa −1,400 m. Se adopta sección; pendiente de aclaración.
Cimentación del vaporizador LV1802C · pedestal DZ8 1 | Parcela industrial Jinhong | Cimentación industrial | Cimentaciones de equipos y pedestales del fabricante · revisión recibida 04/09/2026 | 1.00058 | 0.915129 | 1.865 | 7.781 | 1.3428 | process_plant | Zona de separación de aire | {"name":"Hormigón armado · clase pendiente de confirmar","status":"Clase no confirmada en la hoja de equipo","source":"Geometría de cimentación del fabricante; no se extrapola HA-30 de la nota de pedestales."} | {"documented":[{"label":"Extensión local X","value":0.9,"unit":"m","source":"2719/25CB, 2719/E3A8, 1FEC2","status":"derivada del contorno CAD"},{"label":"Extensión local Y","value":0.8,"unit":"m","source":"2719/25CB, 2719/E3A8, 1FEC2","status":"derivada del contorno CAD"},{"label":"Cota inferior relativa adoptada","value":-1.4,"unit":"m","source":"8–8","status":"interpretación con conflicto conservado"},{"label":"Cota superior relativa adoptada","value":0.465,"unit":"m","source":"8–8","status":"documentada / separación por material"}],"geometry":[{"label":"Extensión de la malla en X","value":1.0005759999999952,"unit":"m","source":"Geometría releída del IFC; datum absoluto de proceso provisional","status":"derivado"},{"label":"Extensión de la malla en Y","value":0.9151290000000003,"unit":"m","source":"Geometría releída del IFC; datum absoluto de proceso provisional","status":"derivado"},{"label":"Extensión de la malla en Z","value":1.865,"unit":"m","source":"Geometría releída del IFC; datum absoluto de proceso provisional","status":"derivado"},{"label":"Cota inferior de visualización","value":284.7,"unit":"m","source":"Geometría releída del IFC; datum absoluto de proceso provisional","status":"derivado"},{"label":"Cota superior de visualización","value":286.565,"unit":"m","source":"Geometría releída del IFC; datum absoluto de proceso provisional","status":"derivado"}]} | {"documentId":"LHD2609-JG00100-20260904","title":"Cimentaciones de equipos y pedestales del fabricante · revisión recibida 04/09/2026","date":"2026-09-04","sheet":"8–8","fileName":"LHD2609-JG00100_20260904.dwg","revisionCaveat":"Fecha de revisión tomada del nombre recibido; cajetines internos mantienen 02/07/2026 y algunos textos de plantilla.","sourceFileSha256":"b42eb027b7bc0b14c38d1d13514f4899b58a732aa8d0ba2ccf10fa2fc3192890"} | provisional | ["Planta: −2,400 m. Sección 8–8: fondo −2,000 m, coronación de losa −1,400 m. Se adopta sección; pendiente de aclaración."] | {"Cota inferior relativa (m)":-1.4,"Cota superior relativa (m)":0.465,"Cero absoluto de visualización (m)":286.1,"Estado del cero absoluto":"Provisional","Criterio":"Las cotas relativas proceden del dibujo; la equivalencia absoluta no está confirmada."} | {"boundingBoxM":{"min":[45.440744,36.483047,-0.3],"max":[46.44132,37.398176,1.565]},"extentsM":[1.000576,0.915129,1.865],"meshSurfaceM2":7.781003,"meshVolumeM3":1.342801,"closedSolid":true,"basis":"Magnitudes de las mallas representadas, no cantidades certificadas de obra, compra o fabricación. Las partes pueden compartir superficies; no se suman como un despiece de materiales."} | {"profileId":"concrete_reinforced","name":"Hormigón armado · gris natural","materialName":"Hormigón armado · clase pendiente de confirmar","physicalMaterialStatus":"Clase no confirmada en la hoja de equipo","physicalMaterialSource":"Geometría de cimentación del fabricante; no se extrapola HA-30 de la nota de pedestales.","appearanceStatus":"criterio_visual","appearanceBasis":"Interpretación visual del material documental; el acabado, tono y parámetros PBR no son una especificación contractual.","note":"La apariencia gráfica no modifica ni confirma la especificación física del material."} | {"elementId":"found_0904_4e3ba53c588b2c","ifcGuid":"36N1pz7mvQb8cUXLEtbqEV","ifcClass":"IfcFooting","buildingId":"process_plant","buildingName":"Zona de separación de aire","sourceDocumentId":"LHD2609-JG00100-20260904","sourceRepresentationKind":"foundation"} | {"layerId":"foundations","layerName":"Cimentaciones","role":"Cimentación industrial","basis":"Clasificación por función del elemento; no modifica las especificaciones documentales."} | {"profileId":"concrete_reinforced","name":"Hormigón armado · gris natural","status":"criterio_visual","basis":"Interpretación visual del material documental; el acabado, tono y parámetros PBR no son una especificación contractual.","physicalMaterialUnchanged":true} | 1.3428 | Hormigón armado · clase pendiente de confirmar | Hormigón armado · gris natural | found_0904_4e3ba53c588b2c | Geometría de cimentación del fabricante; no se extrapola HA-30 de la nota de pedestales. | Clase no confirmada en la hoja de equipo | concrete_reinforced | [0.666667,0.662745,0.619608] | 0.96 | Zona de separación de aire; BIM · Cimentaciones | 1.00058 | 0.915129 | 1.865 | 284.7 | 286.565 | F-LV1802C | ["LV1802C"] | [] | 8–8 | ["2719/25CB","2719/E3A8","1FEC2"] | F-LV1802C/Cimentación del vaporizador LV1802C · pedestal DZ8 1 | foundation | Geometría de fabricante; implantación absoluta provisional | LV1802C | Cimentaciones de equipos y pedestales del fabricante · revisión recibida 04/09/2026 | 2719/25CB, 2719/E3A8, 1FEC2 | -1.4 | 0.465 | 0.72 | Cotas relativas del dibujo. La equivalencia con un datum absoluto está pendiente. | Z del modelo = cota relativa + 1,10 m. Correspondencia provisional con 286,10 m; no es cota de obra confirmada. | Sección y contornos del fabricante; incidencias conservadas | 0.9 | 0.8 | Planta: −2,400 m. Sección 8–8: fondo −2,000 m, coronación de losa −1,400 m. Se adopta sección; pendiente de aclaración.
Cimentación del vaporizador LV1802C · pedestal DZ8 2 | Parcela industrial Jinhong | Cimentación industrial | Cimentaciones de equipos y pedestales del fabricante · revisión recibida 04/09/2026 | 1.00058 | 0.915128 | 1.865 | 7.781 | 1.3428 | process_plant | Zona de separación de aire | {"name":"Hormigón armado · clase pendiente de confirmar","status":"Clase no confirmada en la hoja de equipo","source":"Geometría de cimentación del fabricante; no se extrapola HA-30 de la nota de pedestales."} | {"documented":[{"label":"Extensión local X","value":0.9,"unit":"m","source":"2719/25CB, 2719/E3A8, 1FEC2","status":"derivada del contorno CAD"},{"label":"Extensión local Y","value":0.8,"unit":"m","source":"2719/25CB, 2719/E3A8, 1FEC2","status":"derivada del contorno CAD"},{"label":"Cota inferior relativa adoptada","value":-1.4,"unit":"m","source":"8–8","status":"interpretación con conflicto conservado"},{"label":"Cota superior relativa adoptada","value":0.465,"unit":"m","source":"8–8","status":"documentada / separación por material"}],"geometry":[{"label":"Extensión de la malla en X","value":1.0005760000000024,"unit":"m","source":"Geometría releída del IFC; datum absoluto de proceso provisional","status":"derivado"},{"label":"Extensión de la malla en Y","value":0.9151279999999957,"unit":"m","source":"Geometría releída del IFC; datum absoluto de proceso provisional","status":"derivado"},{"label":"Extensión de la malla en Z","value":1.865,"unit":"m","source":"Geometría releída del IFC; datum absoluto de proceso provisional","status":"derivado"},{"label":"Cota inferior de visualización","value":284.7,"unit":"m","source":"Geometría releída del IFC; datum absoluto de proceso provisional","status":"derivado"},{"label":"Cota superior de visualización","value":286.565,"unit":"m","source":"Geometría releída del IFC; datum absoluto de proceso provisional","status":"derivado"}]} | {"documentId":"LHD2609-JG00100-20260904","title":"Cimentaciones de equipos y pedestales del fabricante · revisión recibida 04/09/2026","date":"2026-09-04","sheet":"8–8","fileName":"LHD2609-JG00100_20260904.dwg","revisionCaveat":"Fecha de revisión tomada del nombre recibido; cajetines internos mantienen 02/07/2026 y algunos textos de plantilla.","sourceFileSha256":"b42eb027b7bc0b14c38d1d13514f4899b58a732aa8d0ba2ccf10fa2fc3192890"} | provisional | ["Planta: −2,400 m. Sección 8–8: fondo −2,000 m, coronación de losa −1,400 m. Se adopta sección; pendiente de aclaración."] | {"Cota inferior relativa (m)":-1.4,"Cota superior relativa (m)":0.465,"Cero absoluto de visualización (m)":286.1,"Estado del cero absoluto":"Provisional","Criterio":"Las cotas relativas proceden del dibujo; la equivalencia absoluta no está confirmada."} | {"boundingBoxM":{"min":[47.955092,36.137362,-0.3],"max":[48.955668,37.05249,1.565]},"extentsM":[1.000576,0.915128,1.865],"meshSurfaceM2":7.781003,"meshVolumeM3":1.342801,"closedSolid":true,"basis":"Magnitudes de las mallas representadas, no cantidades certificadas de obra, compra o fabricación. Las partes pueden compartir superficies; no se suman como un despiece de materiales."} | {"profileId":"concrete_reinforced","name":"Hormigón armado · gris natural","materialName":"Hormigón armado · clase pendiente de confirmar","physicalMaterialStatus":"Clase no confirmada en la hoja de equipo","physicalMaterialSource":"Geometría de cimentación del fabricante; no se extrapola HA-30 de la nota de pedestales.","appearanceStatus":"criterio_visual","appearanceBasis":"Interpretación visual del material documental; el acabado, tono y parámetros PBR no son una especificación contractual.","note":"La apariencia gráfica no modifica ni confirma la especificación física del material."} | {"elementId":"found_0904_253a35067636ca","ifcGuid":"14DV4OWKnJw96i2rRyCkbl","ifcClass":"IfcFooting","buildingId":"process_plant","buildingName":"Zona de separación de aire","sourceDocumentId":"LHD2609-JG00100-20260904","sourceRepresentationKind":"foundation"} | {"layerId":"foundations","layerName":"Cimentaciones","role":"Cimentación industrial","basis":"Clasificación por función del elemento; no modifica las especificaciones documentales."} | {"profileId":"concrete_reinforced","name":"Hormigón armado · gris natural","status":"criterio_visual","basis":"Interpretación visual del material documental; el acabado, tono y parámetros PBR no son una especificación contractual.","physicalMaterialUnchanged":true} | 1.3428 | Hormigón armado · clase pendiente de confirmar | Hormigón armado · gris natural | found_0904_253a35067636ca | Geometría de cimentación del fabricante; no se extrapola HA-30 de la nota de pedestales. | Clase no confirmada en la hoja de equipo | concrete_reinforced | [0.666667,0.662745,0.619608] | 0.96 | Zona de separación de aire; BIM · Cimentaciones | 1.00058 | 0.915128 | 1.865 | 284.7 | 286.565 | F-LV1802C | ["LV1802C"] | [] | 8–8 | ["2719/25CB","2719/E3A8","1FEC2"] | F-LV1802C/Cimentación del vaporizador LV1802C · pedestal DZ8 2 | foundation | Geometría de fabricante; implantación absoluta provisional | LV1802C | Cimentaciones de equipos y pedestales del fabricante · revisión recibida 04/09/2026 | 2719/25CB, 2719/E3A8, 1FEC2 | -1.4 | 0.465 | 0.72 | Cotas relativas del dibujo. La equivalencia con un datum absoluto está pendiente. | Z del modelo = cota relativa + 1,10 m. Correspondencia provisional con 286,10 m; no es cota de obra confirmada. | Sección y contornos del fabricante; incidencias conservadas | 0.9 | 0.8 | Planta: −2,400 m. Sección 8–8: fondo −2,000 m, coronación de losa −1,400 m. Se adopta sección; pendiente de aclaración.
Cimentación del vaporizador LV1802C · pedestal DZ8 3 | Parcela industrial Jinhong | Cimentación industrial | Cimentaciones de equipos y pedestales del fabricante · revisión recibida 04/09/2026 | 1.00058 | 0.915128 | 1.865 | 7.781 | 1.3428 | process_plant | Zona de separación de aire | {"name":"Hormigón armado · clase pendiente de confirmar","status":"Clase no confirmada en la hoja de equipo","source":"Geometría de cimentación del fabricante; no se extrapola HA-30 de la nota de pedestales."} | {"documented":[{"label":"Extensión local X","value":0.9,"unit":"m","source":"2719/25CB, 2719/E3A8, 1FEC2","status":"derivada del contorno CAD"},{"label":"Extensión local Y","value":0.8,"unit":"m","source":"2719/25CB, 2719/E3A8, 1FEC2","status":"derivada del contorno CAD"},{"label":"Cota inferior relativa adoptada","value":-1.4,"unit":"m","source":"8–8","status":"interpretación con conflicto conservado"},{"label":"Cota superior relativa adoptada","value":0.465,"unit":"m","source":"8–8","status":"documentada / separación por material"}],"geometry":[{"label":"Extensión de la malla en X","value":1.0005760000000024,"unit":"m","source":"Geometría releída del IFC; datum absoluto de proceso provisional","status":"derivado"},{"label":"Extensión de la malla en Y","value":0.9151279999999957,"unit":"m","source":"Geometría releída del IFC; datum absoluto de proceso provisional","status":"derivado"},{"label":"Extensión de la malla en Z","value":1.865,"unit":"m","source":"Geometría releída del IFC; datum absoluto de proceso provisional","status":"derivado"},{"label":"Cota inferior de visualización","value":284.7,"unit":"m","source":"Geometría releída del IFC; datum absoluto de proceso provisional","status":"derivado"},{"label":"Cota superior de visualización","value":286.565,"unit":"m","source":"Geometría releída del IFC; datum absoluto de proceso provisional","status":"derivado"}]} | {"documentId":"LHD2609-JG00100-20260904","title":"Cimentaciones de equipos y pedestales del fabricante · revisión recibida 04/09/2026","date":"2026-09-04","sheet":"8–8","fileName":"LHD2609-JG00100_20260904.dwg","revisionCaveat":"Fecha de revisión tomada del nombre recibido; cajetines internos mantienen 02/07/2026 y algunos textos de plantilla.","sourceFileSha256":"b42eb027b7bc0b14c38d1d13514f4899b58a732aa8d0ba2ccf10fa2fc3192890"} | provisional | ["Planta: −2,400 m. Sección 8–8: fondo −2,000 m, coronación de losa −1,400 m. Se adopta sección; pendiente de aclaración."] | {"Cota inferior relativa (m)":-1.4,"Cota superior relativa (m)":0.465,"Cero absoluto de visualización (m)":286.1,"Estado del cero absoluto":"Provisional","Criterio":"Las cotas relativas proceden del dibujo; la equivalencia absoluta no está confirmada."} | {"boundingBoxM":{"min":[47.686226,34.181758,-0.3],"max":[48.686802,35.096886,1.565]},"extentsM":[1.000576,0.915128,1.865],"meshSurfaceM2":7.781,"meshVolumeM3":1.3428,"closedSolid":true,"basis":"Magnitudes de las mallas representadas, no cantidades certificadas de obra, compra o fabricación. Las partes pueden compartir superficies; no se suman como un despiece de materiales."} | {"profileId":"concrete_reinforced","name":"Hormigón armado · gris natural","materialName":"Hormigón armado · clase pendiente de confirmar","physicalMaterialStatus":"Clase no confirmada en la hoja de equipo","physicalMaterialSource":"Geometría de cimentación del fabricante; no se extrapola HA-30 de la nota de pedestales.","appearanceStatus":"criterio_visual","appearanceBasis":"Interpretación visual del material documental; el acabado, tono y parámetros PBR no son una especificación contractual.","note":"La apariencia gráfica no modifica ni confirma la especificación física del material."} | {"elementId":"found_0904_c45eec1ff6ea2b","ifcGuid":"3a0zbswGvVme15reMQ$WKv","ifcClass":"IfcFooting","buildingId":"process_plant","buildingName":"Zona de separación de aire","sourceDocumentId":"LHD2609-JG00100-20260904","sourceRepresentationKind":"foundation"} | {"layerId":"foundations","layerName":"Cimentaciones","role":"Cimentación industrial","basis":"Clasificación por función del elemento; no modifica las especificaciones documentales."} | {"profileId":"concrete_reinforced","name":"Hormigón armado · gris natural","status":"criterio_visual","basis":"Interpretación visual del material documental; el acabado, tono y parámetros PBR no son una especificación contractual.","physicalMaterialUnchanged":true} | 1.3428 | Hormigón armado · clase pendiente de confirmar | Hormigón armado · gris natural | found_0904_c45eec1ff6ea2b | Geometría de cimentación del fabricante; no se extrapola HA-30 de la nota de pedestales. | Clase no confirmada en la hoja de equipo | concrete_reinforced | [0.666667,0.662745,0.619608] | 0.96 | Zona de separación de aire; BIM · Cimentaciones | 1.00058 | 0.915128 | 1.865 | 284.7 | 286.565 | F-LV1802C | ["LV1802C"] | [] | 8–8 | ["2719/25CB","2719/E3A8","1FEC2"] | F-LV1802C/Cimentación del vaporizador LV1802C · pedestal DZ8 3 | foundation | Geometría de fabricante; implantación absoluta provisional | LV1802C | Cimentaciones de equipos y pedestales del fabricante · revisión recibida 04/09/2026 | 2719/25CB, 2719/E3A8, 1FEC2 | -1.4 | 0.465 | 0.72 | Cotas relativas del dibujo. La equivalencia con un datum absoluto está pendiente. | Z del modelo = cota relativa + 1,10 m. Correspondencia provisional con 286,10 m; no es cota de obra confirmada. | Sección y contornos del fabricante; incidencias conservadas | 0.9 | 0.8 | Planta: −2,400 m. Sección 8–8: fondo −2,000 m, coronación de losa −1,400 m. Se adopta sección; pendiente de aclaración.
Cimentación del vaporizador LV1802C · pedestal DZ8 4 | Parcela industrial Jinhong | Cimentación industrial | Cimentaciones de equipos y pedestales del fabricante · revisión recibida 04/09/2026 | 1.00058 | 0.915128 | 1.865 | 7.781 | 1.3428 | process_plant | Zona de separación de aire | {"name":"Hormigón armado · clase pendiente de confirmar","status":"Clase no confirmada en la hoja de equipo","source":"Geometría de cimentación del fabricante; no se extrapola HA-30 de la nota de pedestales."} | {"documented":[{"label":"Extensión local X","value":0.9,"unit":"m","source":"2719/25CB, 2719/E3A8, 1FEC2","status":"derivada del contorno CAD"},{"label":"Extensión local Y","value":0.8,"unit":"m","source":"2719/25CB, 2719/E3A8, 1FEC2","status":"derivada del contorno CAD"},{"label":"Cota inferior relativa adoptada","value":-1.4,"unit":"m","source":"8–8","status":"interpretación con conflicto conservado"},{"label":"Cota superior relativa adoptada","value":0.465,"unit":"m","source":"8–8","status":"documentada / separación por material"}],"geometry":[{"label":"Extensión de la malla en X","value":1.0005760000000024,"unit":"m","source":"Geometría releída del IFC; datum absoluto de proceso provisional","status":"derivado"},{"label":"Extensión de la malla en Y","value":0.9151279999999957,"unit":"m","source":"Geometría releída del IFC; datum absoluto de proceso provisional","status":"derivado"},{"label":"Extensión de la malla en Z","value":1.865,"unit":"m","source":"Geometría releída del IFC; datum absoluto de proceso provisional","status":"derivado"},{"label":"Cota inferior de visualización","value":284.7,"unit":"m","source":"Geometría releída del IFC; datum absoluto de proceso provisional","status":"derivado"},{"label":"Cota superior de visualización","value":286.565,"unit":"m","source":"Geometría releída del IFC; datum absoluto de proceso provisional","status":"derivado"}]} | {"documentId":"LHD2609-JG00100-20260904","title":"Cimentaciones de equipos y pedestales del fabricante · revisión recibida 04/09/2026","date":"2026-09-04","sheet":"8–8","fileName":"LHD2609-JG00100_20260904.dwg","revisionCaveat":"Fecha de revisión tomada del nombre recibido; cajetines internos mantienen 02/07/2026 y algunos textos de plantilla.","sourceFileSha256":"b42eb027b7bc0b14c38d1d13514f4899b58a732aa8d0ba2ccf10fa2fc3192890"} | provisional | ["Planta: −2,400 m. Sección 8–8: fondo −2,000 m, coronación de losa −1,400 m. Se adopta sección; pendiente de aclaración."] | {"Cota inferior relativa (m)":-1.4,"Cota superior relativa (m)":0.465,"Cero absoluto de visualización (m)":286.1,"Estado del cero absoluto":"Provisional","Criterio":"Las cotas relativas proceden del dibujo; la equivalencia absoluta no está confirmada."} | {"boundingBoxM":{"min":[45.171878,34.527444,-0.3],"max":[46.172454,35.442572,1.565]},"extentsM":[1.000576,0.915128,1.865],"meshSurfaceM2":7.780998,"meshVolumeM3":1.342799,"closedSolid":true,"basis":"Magnitudes de las mallas representadas, no cantidades certificadas de obra, compra o fabricación. Las partes pueden compartir superficies; no se suman como un despiece de materiales."} | {"profileId":"concrete_reinforced","name":"Hormigón armado · gris natural","materialName":"Hormigón armado · clase pendiente de confirmar","physicalMaterialStatus":"Clase no confirmada en la hoja de equipo","physicalMaterialSource":"Geometría de cimentación del fabricante; no se extrapola HA-30 de la nota de pedestales.","appearanceStatus":"criterio_visual","appearanceBasis":"Interpretación visual del material documental; el acabado, tono y parámetros PBR no son una especificación contractual.","note":"La apariencia gráfica no modifica ni confirma la especificación física del material."} | {"elementId":"found_0904_16f158bd07b9be","ifcGuid":"3w2dumS$bJcgkyYwEuCRBm","ifcClass":"IfcFooting","buildingId":"process_plant","buildingName":"Zona de separación de aire","sourceDocumentId":"LHD2609-JG00100-20260904","sourceRepresentationKind":"foundation"} | {"layerId":"foundations","layerName":"Cimentaciones","role":"Cimentación industrial","basis":"Clasificación por función del elemento; no modifica las especificaciones documentales."} | {"profileId":"concrete_reinforced","name":"Hormigón armado · gris natural","status":"criterio_visual","basis":"Interpretación visual del material documental; el acabado, tono y parámetros PBR no son una especificación contractual.","physicalMaterialUnchanged":true} | 1.3428 | Hormigón armado · clase pendiente de confirmar | Hormigón armado · gris natural | found_0904_16f158bd07b9be | Geometría de cimentación del fabricante; no se extrapola HA-30 de la nota de pedestales. | Clase no confirmada en la hoja de equipo | concrete_reinforced | [0.666667,0.662745,0.619608] | 0.96 | Zona de separación de aire; BIM · Cimentaciones | 1.00058 | 0.915128 | 1.865 | 284.7 | 286.565 | F-LV1802C | ["LV1802C"] | [] | 8–8 | ["2719/25CB","2719/E3A8","1FEC2"] | F-LV1802C/Cimentación del vaporizador LV1802C · pedestal DZ8 4 | foundation | Geometría de fabricante; implantación absoluta provisional | LV1802C | Cimentaciones de equipos y pedestales del fabricante · revisión recibida 04/09/2026 | 2719/25CB, 2719/E3A8, 1FEC2 | -1.4 | 0.465 | 0.72 | Cotas relativas del dibujo. La equivalencia con un datum absoluto está pendiente. | Z del modelo = cota relativa + 1,10 m. Correspondencia provisional con 286,10 m; no es cota de obra confirmada. | Sección y contornos del fabricante; incidencias conservadas | 0.9 | 0.8 | Planta: −2,400 m. Sección 8–8: fondo −2,000 m, coronación de losa −1,400 m. Se adopta sección; pendiente de aclaración.
Cimentación del vaporizador LV1802C · pedestal DZ8 5 | Parcela industrial Jinhong | Cimentación industrial | Cimentaciones de equipos y pedestales del fabricante · revisión recibida 04/09/2026 | 1.00058 | 0.915129 | 1.865 | 7.781 | 1.3428 | process_plant | Zona de separación de aire | {"name":"Hormigón armado · clase pendiente de confirmar","status":"Clase no confirmada en la hoja de equipo","source":"Geometría de cimentación del fabricante; no se extrapola HA-30 de la nota de pedestales."} | {"documented":[{"label":"Extensión local X","value":0.9,"unit":"m","source":"2719/25CB, 2719/E3A8, 1FEC2","status":"derivada del contorno CAD"},{"label":"Extensión local Y","value":0.8,"unit":"m","source":"2719/25CB, 2719/E3A8, 1FEC2","status":"derivada del contorno CAD"},{"label":"Cota inferior relativa adoptada","value":-1.4,"unit":"m","source":"8–8","status":"interpretación con conflicto conservado"},{"label":"Cota superior relativa adoptada","value":0.465,"unit":"m","source":"8–8","status":"documentada / separación por material"}],"geometry":[{"label":"Extensión de la malla en X","value":1.0005759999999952,"unit":"m","source":"Geometría releída del IFC; datum absoluto de proceso provisional","status":"derivado"},{"label":"Extensión de la malla en Y","value":0.9151290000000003,"unit":"m","source":"Geometría releída del IFC; datum absoluto de proceso provisional","status":"derivado"},{"label":"Extensión de la malla en Z","value":1.865,"unit":"m","source":"Geometría releída del IFC; datum absoluto de proceso provisional","status":"derivado"},{"label":"Cota inferior de visualización","value":284.7,"unit":"m","source":"Geometría releída del IFC; datum absoluto de proceso provisional","status":"derivado"},{"label":"Cota superior de visualización","value":286.565,"unit":"m","source":"Geometría releída del IFC; datum absoluto de proceso provisional","status":"derivado"}]} | {"documentId":"LHD2609-JG00100-20260904","title":"Cimentaciones de equipos y pedestales del fabricante · revisión recibida 04/09/2026","date":"2026-09-04","sheet":"8–8","fileName":"LHD2609-JG00100_20260904.dwg","revisionCaveat":"Fecha de revisión tomada del nombre recibido; cajetines internos mantienen 02/07/2026 y algunos textos de plantilla.","sourceFileSha256":"b42eb027b7bc0b14c38d1d13514f4899b58a732aa8d0ba2ccf10fa2fc3192890"} | provisional | ["Planta: −2,400 m. Sección 8–8: fondo −2,000 m, coronación de losa −1,400 m. Se adopta sección; pendiente de aclaración."] | {"Cota inferior relativa (m)":-1.4,"Cota superior relativa (m)":0.465,"Cero absoluto de visualización (m)":286.1,"Estado del cero absoluto":"Provisional","Criterio":"Las cotas relativas proceden del dibujo; la equivalencia absoluta no está confirmada."} | {"boundingBoxM":{"min":[46.404594,35.211921,-0.3],"max":[47.40517,36.12705,1.565]},"extentsM":[1.000576,0.915129,1.865],"meshSurfaceM2":7.781003,"meshVolumeM3":1.342801,"closedSolid":true,"basis":"Magnitudes de las mallas representadas, no cantidades certificadas de obra, compra o fabricación. Las partes pueden compartir superficies; no se suman como un despiece de materiales."} | {"profileId":"concrete_reinforced","name":"Hormigón armado · gris natural","materialName":"Hormigón armado · clase pendiente de confirmar","physicalMaterialStatus":"Clase no confirmada en la hoja de equipo","physicalMaterialSource":"Geometría de cimentación del fabricante; no se extrapola HA-30 de la nota de pedestales.","appearanceStatus":"criterio_visual","appearanceBasis":"Interpretación visual del material documental; el acabado, tono y parámetros PBR no son una especificación contractual.","note":"La apariencia gráfica no modifica ni confirma la especificación física del material."} | {"elementId":"found_0904_6b497236897623","ifcGuid":"0GKjHB5ojLVBXIRnBMpe0f","ifcClass":"IfcFooting","buildingId":"process_plant","buildingName":"Zona de separación de aire","sourceDocumentId":"LHD2609-JG00100-20260904","sourceRepresentationKind":"foundation"} | {"layerId":"foundations","layerName":"Cimentaciones","role":"Cimentación industrial","basis":"Clasificación por función del elemento; no modifica las especificaciones documentales."} | {"profileId":"concrete_reinforced","name":"Hormigón armado · gris natural","status":"criterio_visual","basis":"Interpretación visual del material documental; el acabado, tono y parámetros PBR no son una especificación contractual.","physicalMaterialUnchanged":true} | 1.3428 | Hormigón armado · clase pendiente de confirmar | Hormigón armado · gris natural | found_0904_6b497236897623 | Geometría de cimentación del fabricante; no se extrapola HA-30 de la nota de pedestales. | Clase no confirmada en la hoja de equipo | concrete_reinforced | [0.666667,0.662745,0.619608] | 0.96 | Zona de separación de aire; BIM · Cimentaciones | 1.00058 | 0.915129 | 1.865 | 284.7 | 286.565 | F-LV1802C | ["LV1802C"] | [] | 8–8 | ["2719/25CB","2719/E3A8","1FEC2"] | F-LV1802C/Cimentación del vaporizador LV1802C · pedestal DZ8 5 | foundation | Geometría de fabricante; implantación absoluta provisional | LV1802C | Cimentaciones de equipos y pedestales del fabricante · revisión recibida 04/09/2026 | 2719/25CB, 2719/E3A8, 1FEC2 | -1.4 | 0.465 | 0.72 | Cotas relativas del dibujo. La equivalencia con un datum absoluto está pendiente. | Z del modelo = cota relativa + 1,10 m. Correspondencia provisional con 286,10 m; no es cota de obra confirmada. | Sección y contornos del fabricante; incidencias conservadas | 0.9 | 0.8 | Planta: −2,400 m. Sección 8–8: fondo −2,000 m, coronación de losa −1,400 m. Se adopta sección; pendiente de aclaración.
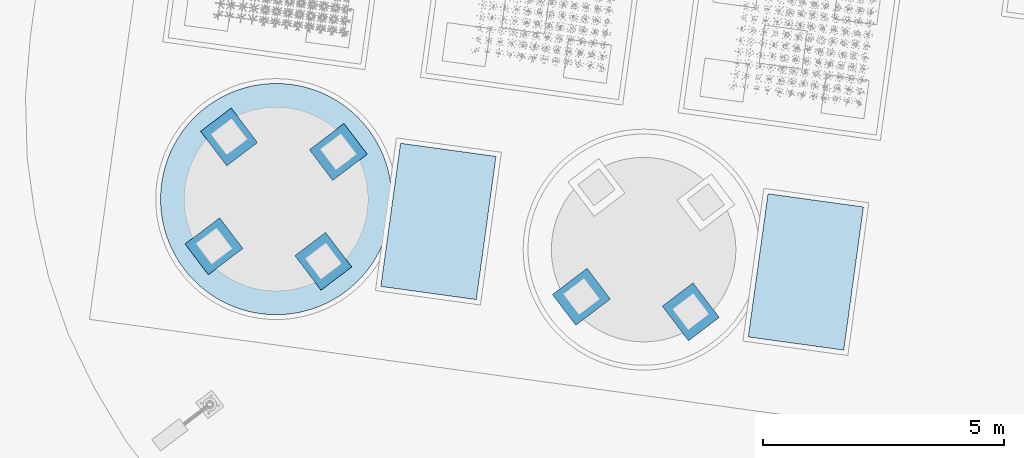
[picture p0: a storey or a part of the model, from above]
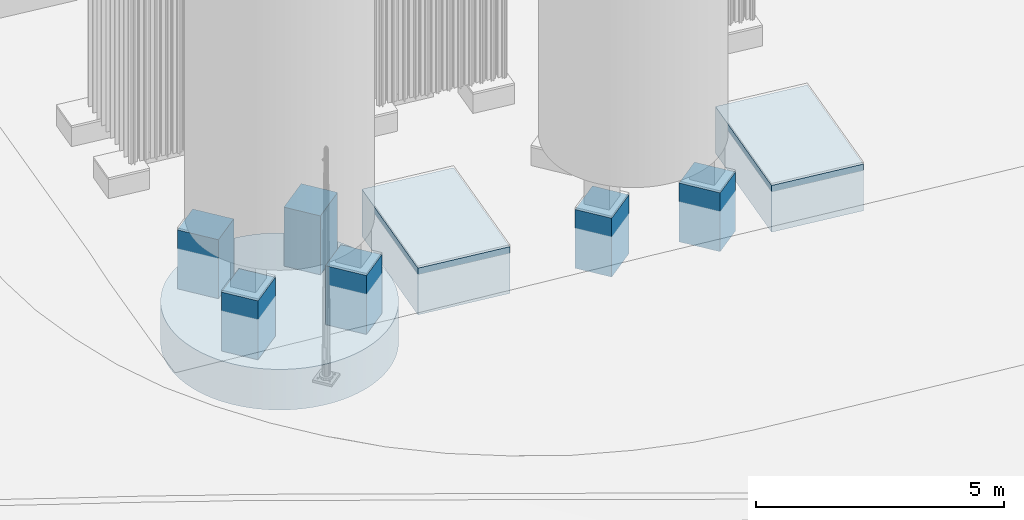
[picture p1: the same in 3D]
Properties of the parts of a building model (IFC4), part 70 of 134

# IfcFooting (214)
Name | In | Description = category = Categoria = Funcion | Document | ExtensionX (m) | ExtensionY (m) | ExtensionZ (m) | SuperficieDeLaMalla (m2) | VolumenGeometrico (m3) | buildingId | buildingName | material | dimensions | JH_InformacionBIM, source = DocumentoFuente | JH_InformacionBIM, status = EstadoDeInformacion | issues = IncidenciasPendientes | positioning = PosicionYEstado | geometryMetrics | materialAppearance | visualizationIdentity | classification | appearance | Volumen geométrico (m³) | JH_Trazabilidad, Material = name | Acabado de visualización = Acabado | Identificador | JH_EvidenciaDeMaterial, source | JH_EvidenciaDeMaterial, status | Perfil | ColorRGB | Rugosidad | Group | Extensión de la malla en X (m) | Extensión de la malla en Y (m) | Extensión de la malla en Z (m) = Espesor o altura real de sección (m) | Cota inferior de visualización (m) | Cota superior de visualización (m) | assemblyId = Conjunto de cimentación | equipmentIds | supportPositionIds | sectionRef = Sección de referencia | sourceCadHandles | stableElementKey | representationKind | geometryStatus | Equipos asociados | Documento de origen | Identificadores CAD de referencia | Cota inferior relativa (m) = Cota inferior relativa adoptada (m) | Cota superior relativa (m) = Cota superior relativa adoptada (m) | Área de planta (m²) | Referencia vertical | Implantación para visualización | Estado de la geometría | Extensión local X (m) | Extensión local Y (m) | Incidencias de origen
Cimentación común de torres de refrigeración · cuerpo de hormigón | Parcela industrial Jinhong | Cimentación industrial | Cimentaciones de equipos y pedestales del fabricante · revisión recibida 04/09/2026 | 7.37251 | 9.72233 | 0.8 | 135.555 | 44.5133 | process_plant | Zona de separación de aire | {"name":"Hormigón armado · clase pendiente de confirmar","status":"Clase no confirmada en la hoja de equipo","source":"Geometría de cimentación del fabricante; no se extrapola HA-30 de la nota de pedestales."} | {"documented":[{"label":"Extensión local X","value":6.21,"unit":"m","source":"25DC/25E1, 25DC/25E2, 25DC/25E4, 25DC/2604, 25DC/25E5, 2473E","status":"derivada del contorno CAD"},{"label":"Extensión local Y","value":8.96,"unit":"m","source":"25DC/25E1, 25DC/25E2, 25DC/25E4, 25DC/2604, 25DC/25E5, 2473E","status":"derivada del contorno CAD"},{"label":"Cota inferior relativa adoptada","value":-2,"unit":"m","source":"9–9 / 9A–9A","status":"interpretación con conflicto conservado"},{"label":"Cota superior relativa adoptada","value":-1.2,"unit":"m","source":"9–9 / 9A–9A","status":"documentada / separación por material"}],"geometry":[{"label":"Extensión de la malla en X","value":7.372515,"unit":"m","source":"Geometría releída del IFC; datum absoluto de proceso provisional","status":"derivado"},{"label":"Extensión de la malla en Y","value":9.722327,"unit":"m","source":"Geometría releída del IFC; datum absoluto de proceso provisional","status":"derivado"},{"label":"Extensión de la malla en Z","value":0.8,"unit":"m","source":"Geometría releída del IFC; datum absoluto de proceso provisional","status":"derivado"},{"label":"Cota inferior de visualización","value":284.1,"unit":"m","source":"Geometría releída del IFC; datum absoluto de proceso provisional","status":"derivado"},{"label":"Cota superior de visualización","value":284.9,"unit":"m","source":"Geometría releída del IFC; datum absoluto de proceso provisional","status":"derivado"}]} | {"documentId":"LHD2609-JG00100-20260904","title":"Cimentaciones de equipos y pedestales del fabricante · revisión recibida 04/09/2026","date":"2026-09-04","sheet":"9–9 / 9A–9A","fileName":"LHD2609-JG00100_20260904.dwg","revisionCaveat":"Fecha de revisión tomada del nombre recibido; cajetines internos mantienen 02/07/2026 y algunos textos de plantilla.","sourceFileSha256":"b42eb027b7bc0b14c38d1d13514f4899b58a732aa8d0ba2ccf10fa2fc3192890"} | provisional | ["Planta: −2,200 m. Secciones: fondo −2,000 m, losa superior −1,200 m; se adoptan secciones.","La última línea transversal presenta una discrepancia de 4 mm respecto a los ejes de pilares; se conserva la posición de cada contorno fuente."] | {"Cota inferior relativa (m)":-2,"Cota superior relativa (m)":-1.2,"Cero absoluto de visualización (m)":286.1,"Estado del cero absoluto":"Provisional","Criterio":"Las cotas relativas proceden del dibujo; la equivalencia absoluta no está confirmada."} | {"boundingBoxM":{"min":[35.656364,41.881525,-0.9],"max":[43.028879,51.603852,-0.1]},"extentsM":[7.372515,9.722327,0.8],"meshSurfaceM2":135.555207,"meshVolumeM3":44.513282,"closedSolid":true,"basis":"Magnitudes de las mallas representadas, no cantidades certificadas de obra, compra o fabricación. Las partes pueden compartir superficies; no se suman como un despiece de materiales."} | {"profileId":"concrete_reinforced","name":"Hormigón armado · gris natural","materialName":"Hormigón armado · clase pendiente de confirmar","physicalMaterialStatus":"Clase no confirmada en la hoja de equipo","physicalMaterialSource":"Geometría de cimentación del fabricante; no se extrapola HA-30 de la nota de pedestales.","appearanceStatus":"criterio_visual","appearanceBasis":"Interpretación visual del material documental; el acabado, tono y parámetros PBR no son una especificación contractual.","note":"La apariencia gráfica no modifica ni confirma la especificación física del material."} | {"elementId":"found_0904_8e2dc98348483c","ifcGuid":"0TQK_kn3fLRwTRzxXO1aL3","ifcClass":"IfcFooting","buildingId":"process_plant","buildingName":"Zona de separación de aire","sourceDocumentId":"LHD2609-JG00100-20260904","sourceRepresentationKind":"foundation"} | {"layerId":"foundations","layerName":"Cimentaciones","role":"Cimentación industrial","basis":"Clasificación por función del elemento; no modifica las especificaciones documentales."} | {"profileId":"concrete_reinforced","name":"Hormigón armado · gris natural","status":"criterio_visual","basis":"Interpretación visual del material documental; el acabado, tono y parámetros PBR no son una especificación contractual.","physicalMaterialUnchanged":true} | 44.5133 | Hormigón armado · clase pendiente de confirmar | Hormigón armado · gris natural | found_0904_8e2dc98348483c | Geometría de cimentación del fabricante; no se extrapola HA-30 de la nota de pedestales. | Clase no confirmada en la hoja de equipo | concrete_reinforced | [0.666667,0.662745,0.619608] | 0.96 | Zona de separación de aire; BIM · Cimentaciones | 7.37251 | 9.72233 | 0.8 | 284.1 | 284.9 | F-WT3001 | ["WT3001A","WT3001B","WT3001C","WT3001D"] | [] | 9–9 / 9A–9A | ["25DC/25E1","25DC/25E2","25DC/25E4","25DC/2604","25DC/25E5","2473E"] | F-WT3001/Cimentación común de torres de refrigeración · cuerpo de hormigón | foundation | Geometría de fabricante; implantación absoluta provisional | WT3001A, WT3001B, WT3001C, WT3001D | Cimentaciones de equipos y pedestales del fabricante · revisión recibida 04/09/2026 | 25DC/25E1, 25DC/25E2, 25DC/25E4, 25DC/2604, 25DC/25E5, 2473E | -2 | -1.2 | 55.6416 | Cotas relativas del dibujo. La equivalencia con un datum absoluto está pendiente. | Z del modelo = cota relativa + 1,10 m. Correspondencia provisional con 286,10 m; no es cota de obra confirmada. | Sección y contornos del fabricante; incidencias conservadas | 6.21 | 8.96 | Planta: −2,200 m. Secciones: fondo −2,000 m, losa superior −1,200 m; se adoptan secciones. / La última línea transversal presenta una discrepancia de 4 mm respecto a los ejes de pilares; se conserva la posición de cada contorno fuente.
Cimentación común de torres de refrigeración · murete transversal 1 | Parcela industrial Jinhong | Cimentación industrial | Cimentaciones de equipos y pedestales del fabricante · revisión recibida 04/09/2026 | 6.20661 | 1.2421 | 2.2 | 34.052 | 5.4648 | process_plant | Zona de separación de aire | {"name":"Hormigón armado · clase pendiente de confirmar","status":"Clase no confirmada en la hoja de equipo","source":"Geometría de cimentación del fabricante; no se extrapola HA-30 de la nota de pedestales."} | {"documented":[{"label":"Extensión local X","value":6.21,"unit":"m","source":"25DC/25E1, 25DC/25E2, 25DC/25E4, 25DC/2604, 25DC/25E5, 2473E","status":"derivada del contorno CAD"},{"label":"Extensión local Y","value":0.4,"unit":"m","source":"25DC/25E1, 25DC/25E2, 25DC/25E4, 25DC/2604, 25DC/25E5, 2473E","status":"derivada del contorno CAD"},{"label":"Cota inferior relativa adoptada","value":-1.2,"unit":"m","source":"9–9 / 9A–9A","status":"interpretación con conflicto conservado"},{"label":"Cota superior relativa adoptada","value":1,"unit":"m","source":"9–9 / 9A–9A","status":"documentada / separación por material"}],"geometry":[{"label":"Extensión de la malla en X","value":6.206609,"unit":"m","source":"Geometría releída del IFC; datum absoluto de proceso provisional","status":"derivado"},{"label":"Extensión de la malla en Y","value":1.2420990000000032,"unit":"m","source":"Geometría releída del IFC; datum absoluto de proceso provisional","status":"derivado"},{"label":"Extensión de la malla en Z","value":2.2,"unit":"m","source":"Geometría releída del IFC; datum absoluto de proceso provisional","status":"derivado"},{"label":"Cota inferior de visualización","value":284.9,"unit":"m","source":"Geometría releída del IFC; datum absoluto de proceso provisional","status":"derivado"},{"label":"Cota superior de visualización","value":287.1,"unit":"m","source":"Geometría releída del IFC; datum absoluto de proceso provisional","status":"derivado"}]} | {"documentId":"LHD2609-JG00100-20260904","title":"Cimentaciones de equipos y pedestales del fabricante · revisión recibida 04/09/2026","date":"2026-09-04","sheet":"9–9 / 9A–9A","fileName":"LHD2609-JG00100_20260904.dwg","revisionCaveat":"Fecha de revisión tomada del nombre recibido; cajetines internos mantienen 02/07/2026 y algunos textos de plantilla.","sourceFileSha256":"b42eb027b7bc0b14c38d1d13514f4899b58a732aa8d0ba2ccf10fa2fc3192890"} | provisional | ["Planta: −2,200 m. Secciones: fondo −2,000 m, losa superior −1,200 m; se adoptan secciones.","La última línea transversal presenta una discrepancia de 4 mm respecto a los ejes de pilares; se conserva la posición de cada contorno fuente."] | {"Cota inferior relativa (m)":-1.2,"Cota superior relativa (m)":1,"Cero absoluto de visualización (m)":286.1,"Estado del cero absoluto":"Provisional","Criterio":"Las cotas relativas proceden del dibujo; la equivalencia absoluta no está confirmada."} | {"boundingBoxM":{"min":[36.82227,50.361753,-0.1],"max":[43.028879,51.603852,2.1]},"extentsM":[6.206609,1.242099,2.2],"meshSurfaceM2":34.052002,"meshVolumeM3":5.464801,"closedSolid":true,"basis":"Magnitudes de las mallas representadas, no cantidades certificadas de obra, compra o fabricación. Las partes pueden compartir superficies; no se suman como un despiece de materiales."} | {"profileId":"concrete_reinforced","name":"Hormigón armado · gris natural","materialName":"Hormigón armado · clase pendiente de confirmar","physicalMaterialStatus":"Clase no confirmada en la hoja de equipo","physicalMaterialSource":"Geometría de cimentación del fabricante; no se extrapola HA-30 de la nota de pedestales.","appearanceStatus":"criterio_visual","appearanceBasis":"Interpretación visual del material documental; el acabado, tono y parámetros PBR no son una especificación contractual.","note":"La apariencia gráfica no modifica ni confirma la especificación física del material."} | {"elementId":"found_0904_eab3135409009d","ifcGuid":"2HcCQZFZbLThiOkxFyRoRC","ifcClass":"IfcFooting","buildingId":"process_plant","buildingName":"Zona de separación de aire","sourceDocumentId":"LHD2609-JG00100-20260904","sourceRepresentationKind":"foundation"} | {"layerId":"foundations","layerName":"Cimentaciones","role":"Cimentación industrial","basis":"Clasificación por función del elemento; no modifica las especificaciones documentales."} | {"profileId":"concrete_reinforced","name":"Hormigón armado · gris natural","status":"criterio_visual","basis":"Interpretación visual del material documental; el acabado, tono y parámetros PBR no son una especificación contractual.","physicalMaterialUnchanged":true} | 5.4648 | Hormigón armado · clase pendiente de confirmar | Hormigón armado · gris natural | found_0904_eab3135409009d | Geometría de cimentación del fabricante; no se extrapola HA-30 de la nota de pedestales. | Clase no confirmada en la hoja de equipo | concrete_reinforced | [0.666667,0.662745,0.619608] | 0.96 | Zona de separación de aire; BIM · Cimentaciones | 6.20661 | 1.2421 | 2.2 | 284.9 | 287.1 | F-WT3001 | ["WT3001A","WT3001B","WT3001C","WT3001D"] | [] | 9–9 / 9A–9A | ["25DC/25E1","25DC/25E2","25DC/25E4","25DC/2604","25DC/25E5","2473E"] | F-WT3001/Cimentación común de torres de refrigeración · murete transversal 1 | foundation | Geometría de fabricante; implantación absoluta provisional | WT3001A, WT3001B, WT3001C, WT3001D | Cimentaciones de equipos y pedestales del fabricante · revisión recibida 04/09/2026 | 25DC/25E1, 25DC/25E2, 25DC/25E4, 25DC/2604, 25DC/25E5, 2473E | -1.2 | 1 | 2.484 | Cotas relativas del dibujo. La equivalencia con un datum absoluto está pendiente. | Z del modelo = cota relativa + 1,10 m. Correspondencia provisional con 286,10 m; no es cota de obra confirmada. | Sección y contornos del fabricante; incidencias conservadas | 6.21 | 0.4 | Planta: −2,200 m. Secciones: fondo −2,000 m, losa superior −1,200 m; se adoptan secciones. / La última línea transversal presenta una discrepancia de 4 mm respecto a los ejes de pilares; se conserva la posición de cada contorno fuente.
Cimentación común de torres de refrigeración · murete transversal 2 | Parcela industrial Jinhong | Cimentación industrial | Cimentaciones de equipos y pedestales del fabricante · revisión recibida 04/09/2026 | 6.20661 | 1.2421 | 2.2 | 34.052 | 5.4648 | process_plant | Zona de separación de aire | {"name":"Hormigón armado · clase pendiente de confirmar","status":"Clase no confirmada en la hoja de equipo","source":"Geometría de cimentación del fabricante; no se extrapola HA-30 de la nota de pedestales."} | {"documented":[{"label":"Extensión local X","value":6.21,"unit":"m","source":"25DC/25E1, 25DC/25E2, 25DC/25E4, 25DC/2604, 25DC/25E5, 2473E","status":"derivada del contorno CAD"},{"label":"Extensión local Y","value":0.4,"unit":"m","source":"25DC/25E1, 25DC/25E2, 25DC/25E4, 25DC/2604, 25DC/25E5, 2473E","status":"derivada del contorno CAD"},{"label":"Cota inferior relativa adoptada","value":-1.2,"unit":"m","source":"9–9 / 9A–9A","status":"interpretación con conflicto conservado"},{"label":"Cota superior relativa adoptada","value":1,"unit":"m","source":"9–9 / 9A–9A","status":"documentada / separación por material"}],"geometry":[{"label":"Extensión de la malla en X","value":6.206609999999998,"unit":"m","source":"Geometría releída del IFC; datum absoluto de proceso provisional","status":"derivado"},{"label":"Extensión de la malla en Y","value":1.2420990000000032,"unit":"m","source":"Geometría releída del IFC; datum absoluto de proceso provisional","status":"derivado"},{"label":"Extensión de la malla en Z","value":2.2,"unit":"m","source":"Geometría releída del IFC; datum absoluto de proceso provisional","status":"derivado"},{"label":"Cota inferior de visualización","value":284.9,"unit":"m","source":"Geometría releída del IFC; datum absoluto de proceso provisional","status":"derivado"},{"label":"Cota superior de visualización","value":287.1,"unit":"m","source":"Geometría releída del IFC; datum absoluto de proceso provisional","status":"derivado"}]} | {"documentId":"LHD2609-JG00100-20260904","title":"Cimentaciones de equipos y pedestales del fabricante · revisión recibida 04/09/2026","date":"2026-09-04","sheet":"9–9 / 9A–9A","fileName":"LHD2609-JG00100_20260904.dwg","revisionCaveat":"Fecha de revisión tomada del nombre recibido; cajetines internos mantienen 02/07/2026 y algunos textos de plantilla.","sourceFileSha256":"b42eb027b7bc0b14c38d1d13514f4899b58a732aa8d0ba2ccf10fa2fc3192890"} | provisional | ["Planta: −2,200 m. Secciones: fondo −2,000 m, losa superior −1,200 m; se adoptan secciones.","La última línea transversal presenta una discrepancia de 4 mm respecto a los ejes de pilares; se conserva la posición de cada contorno fuente."] | {"Cota inferior relativa (m)":-1.2,"Cota superior relativa (m)":1,"Cero absoluto de visualización (m)":286.1,"Estado del cero absoluto":"Provisional","Criterio":"Las cotas relativas proceden del dibujo; la equivalencia absoluta no está confirmada."} | {"boundingBoxM":{"min":[36.530793,48.241696,-0.1],"max":[42.737403,49.483795,2.1]},"extentsM":[6.20661,1.242099,2.2],"meshSurfaceM2":34.052004,"meshVolumeM3":5.464803,"closedSolid":true,"basis":"Magnitudes de las mallas representadas, no cantidades certificadas de obra, compra o fabricación. Las partes pueden compartir superficies; no se suman como un despiece de materiales."} | {"profileId":"concrete_reinforced","name":"Hormigón armado · gris natural","materialName":"Hormigón armado · clase pendiente de confirmar","physicalMaterialStatus":"Clase no confirmada en la hoja de equipo","physicalMaterialSource":"Geometría de cimentación del fabricante; no se extrapola HA-30 de la nota de pedestales.","appearanceStatus":"criterio_visual","appearanceBasis":"Interpretación visual del material documental; el acabado, tono y parámetros PBR no son una especificación contractual.","note":"La apariencia gráfica no modifica ni confirma la especificación física del material."} | {"elementId":"found_0904_5f96c541e7160a","ifcGuid":"0s8uwedaPUq9PKGXrwE4qC","ifcClass":"IfcFooting","buildingId":"process_plant","buildingName":"Zona de separación de aire","sourceDocumentId":"LHD2609-JG00100-20260904","sourceRepresentationKind":"foundation"} | {"layerId":"foundations","layerName":"Cimentaciones","role":"Cimentación industrial","basis":"Clasificación por función del elemento; no modifica las especificaciones documentales."} | {"profileId":"concrete_reinforced","name":"Hormigón armado · gris natural","status":"criterio_visual","basis":"Interpretación visual del material documental; el acabado, tono y parámetros PBR no son una especificación contractual.","physicalMaterialUnchanged":true} | 5.4648 | Hormigón armado · clase pendiente de confirmar | Hormigón armado · gris natural | found_0904_5f96c541e7160a | Geometría de cimentación del fabricante; no se extrapola HA-30 de la nota de pedestales. | Clase no confirmada en la hoja de equipo | concrete_reinforced | [0.666667,0.662745,0.619608] | 0.96 | Zona de separación de aire; BIM · Cimentaciones | 6.20661 | 1.2421 | 2.2 | 284.9 | 287.1 | F-WT3001 | ["WT3001A","WT3001B","WT3001C","WT3001D"] | [] | 9–9 / 9A–9A | ["25DC/25E1","25DC/25E2","25DC/25E4","25DC/2604","25DC/25E5","2473E"] | F-WT3001/Cimentación común de torres de refrigeración · murete transversal 2 | foundation | Geometría de fabricante; implantación absoluta provisional | WT3001A, WT3001B, WT3001C, WT3001D | Cimentaciones de equipos y pedestales del fabricante · revisión recibida 04/09/2026 | 25DC/25E1, 25DC/25E2, 25DC/25E4, 25DC/2604, 25DC/25E5, 2473E | -1.2 | 1 | 2.484 | Cotas relativas del dibujo. La equivalencia con un datum absoluto está pendiente. | Z del modelo = cota relativa + 1,10 m. Correspondencia provisional con 286,10 m; no es cota de obra confirmada. | Sección y contornos del fabricante; incidencias conservadas | 6.21 | 0.4 | Planta: −2,200 m. Secciones: fondo −2,000 m, losa superior −1,200 m; se adoptan secciones. / La última línea transversal presenta una discrepancia de 4 mm respecto a los ejes de pilares; se conserva la posición de cada contorno fuente.
Cimentación común de torres de refrigeración · murete transversal 3 | Parcela industrial Jinhong | Cimentación industrial | Cimentaciones de equipos y pedestales del fabricante · revisión recibida 04/09/2026 | 6.20661 | 1.2421 | 2.2 | 34.052 | 5.4648 | process_plant | Zona de separación de aire | {"name":"Hormigón armado · clase pendiente de confirmar","status":"Clase no confirmada en la hoja de equipo","source":"Geometría de cimentación del fabricante; no se extrapola HA-30 de la nota de pedestales."} | {"documented":[{"label":"Extensión local X","value":6.21,"unit":"m","source":"25DC/25E1, 25DC/25E2, 25DC/25E4, 25DC/2604, 25DC/25E5, 2473E","status":"derivada del contorno CAD"},{"label":"Extensión local Y","value":0.4,"unit":"m","source":"25DC/25E1, 25DC/25E2, 25DC/25E4, 25DC/2604, 25DC/25E5, 2473E","status":"derivada del contorno CAD"},{"label":"Cota inferior relativa adoptada","value":-1.2,"unit":"m","source":"9–9 / 9A–9A","status":"interpretación con conflicto conservado"},{"label":"Cota superior relativa adoptada","value":1,"unit":"m","source":"9–9 / 9A–9A","status":"documentada / separación por material"}],"geometry":[{"label":"Extensión de la malla en X","value":6.206609,"unit":"m","source":"Geometría releída del IFC; datum absoluto de proceso provisional","status":"derivado"},{"label":"Extensión de la malla en Y","value":1.242098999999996,"unit":"m","source":"Geometría releída del IFC; datum absoluto de proceso provisional","status":"derivado"},{"label":"Extensión de la malla en Z","value":2.2,"unit":"m","source":"Geometría releída del IFC; datum absoluto de proceso provisional","status":"derivado"},{"label":"Cota inferior de visualización","value":284.9,"unit":"m","source":"Geometría releída del IFC; datum absoluto de proceso provisional","status":"derivado"},{"label":"Cota superior de visualización","value":287.1,"unit":"m","source":"Geometría releída del IFC; datum absoluto de proceso provisional","status":"derivado"}]} | {"documentId":"LHD2609-JG00100-20260904","title":"Cimentaciones de equipos y pedestales del fabricante · revisión recibida 04/09/2026","date":"2026-09-04","sheet":"9–9 / 9A–9A","fileName":"LHD2609-JG00100_20260904.dwg","revisionCaveat":"Fecha de revisión tomada del nombre recibido; cajetines internos mantienen 02/07/2026 y algunos textos de plantilla.","sourceFileSha256":"b42eb027b7bc0b14c38d1d13514f4899b58a732aa8d0ba2ccf10fa2fc3192890"} | provisional | ["Planta: −2,200 m. Secciones: fondo −2,000 m, losa superior −1,200 m; se adoptan secciones.","La última línea transversal presenta una discrepancia de 4 mm respecto a los ejes de pilares; se conserva la posición de cada contorno fuente."] | {"Cota inferior relativa (m)":-1.2,"Cota superior relativa (m)":1,"Cero absoluto de visualización (m)":286.1,"Estado del cero absoluto":"Provisional","Criterio":"Las cotas relativas proceden del dibujo; la equivalencia absoluta no está confirmada."} | {"boundingBoxM":{"min":[36.239317,46.121639,-0.1],"max":[42.445926,47.363738,2.1]},"extentsM":[6.206609,1.242099,2.2],"meshSurfaceM2":34.052001,"meshVolumeM3":5.464802,"closedSolid":true,"basis":"Magnitudes de las mallas representadas, no cantidades certificadas de obra, compra o fabricación. Las partes pueden compartir superficies; no se suman como un despiece de materiales."} | {"profileId":"concrete_reinforced","name":"Hormigón armado · gris natural","materialName":"Hormigón armado · clase pendiente de confirmar","physicalMaterialStatus":"Clase no confirmada en la hoja de equipo","physicalMaterialSource":"Geometría de cimentación del fabricante; no se extrapola HA-30 de la nota de pedestales.","appearanceStatus":"criterio_visual","appearanceBasis":"Interpretación visual del material documental; el acabado, tono y parámetros PBR no son una especificación contractual.","note":"La apariencia gráfica no modifica ni confirma la especificación física del material."} | {"elementId":"found_0904_0ced5a785cefb0","ifcGuid":"045vSxaLPJ9OaSIXPud5yi","ifcClass":"IfcFooting","buildingId":"process_plant","buildingName":"Zona de separación de aire","sourceDocumentId":"LHD2609-JG00100-20260904","sourceRepresentationKind":"foundation"} | {"layerId":"foundations","layerName":"Cimentaciones","role":"Cimentación industrial","basis":"Clasificación por función del elemento; no modifica las especificaciones documentales."} | {"profileId":"concrete_reinforced","name":"Hormigón armado · gris natural","status":"criterio_visual","basis":"Interpretación visual del material documental; el acabado, tono y parámetros PBR no son una especificación contractual.","physicalMaterialUnchanged":true} | 5.4648 | Hormigón armado · clase pendiente de confirmar | Hormigón armado · gris natural | found_0904_0ced5a785cefb0 | Geometría de cimentación del fabricante; no se extrapola HA-30 de la nota de pedestales. | Clase no confirmada en la hoja de equipo | concrete_reinforced | [0.666667,0.662745,0.619608] | 0.96 | Zona de separación de aire; BIM · Cimentaciones | 6.20661 | 1.2421 | 2.2 | 284.9 | 287.1 | F-WT3001 | ["WT3001A","WT3001B","WT3001C","WT3001D"] | [] | 9–9 / 9A–9A | ["25DC/25E1","25DC/25E2","25DC/25E4","25DC/2604","25DC/25E5","2473E"] | F-WT3001/Cimentación común de torres de refrigeración · murete transversal 3 | foundation | Geometría de fabricante; implantación absoluta provisional | WT3001A, WT3001B, WT3001C, WT3001D | Cimentaciones de equipos y pedestales del fabricante · revisión recibida 04/09/2026 | 25DC/25E1, 25DC/25E2, 25DC/25E4, 25DC/2604, 25DC/25E5, 2473E | -1.2 | 1 | 2.484 | Cotas relativas del dibujo. La equivalencia con un datum absoluto está pendiente. | Z del modelo = cota relativa + 1,10 m. Correspondencia provisional con 286,10 m; no es cota de obra confirmada. | Sección y contornos del fabricante; incidencias conservadas | 6.21 | 0.4 | Planta: −2,200 m. Secciones: fondo −2,000 m, losa superior −1,200 m; se adoptan secciones. / La última línea transversal presenta una discrepancia de 4 mm respecto a los ejes de pilares; se conserva la posición de cada contorno fuente.
Cimentación común de torres de refrigeración · murete transversal 4 | Parcela industrial Jinhong | Cimentación industrial | Cimentaciones de equipos y pedestales del fabricante · revisión recibida 04/09/2026 | 6.20661 | 1.2421 | 2.2 | 34.052 | 5.4648 | process_plant | Zona de separación de aire | {"name":"Hormigón armado · clase pendiente de confirmar","status":"Clase no confirmada en la hoja de equipo","source":"Geometría de cimentación del fabricante; no se extrapola HA-30 de la nota de pedestales."} | {"documented":[{"label":"Extensión local X","value":6.21,"unit":"m","source":"25DC/25E1, 25DC/25E2, 25DC/25E4, 25DC/2604, 25DC/25E5, 2473E","status":"derivada del contorno CAD"},{"label":"Extensión local Y","value":0.4,"unit":"m","source":"25DC/25E1, 25DC/25E2, 25DC/25E4, 25DC/2604, 25DC/25E5, 2473E","status":"derivada del contorno CAD"},{"label":"Cota inferior relativa adoptada","value":-1.2,"unit":"m","source":"9–9 / 9A–9A","status":"interpretación con conflicto conservado"},{"label":"Cota superior relativa adoptada","value":1,"unit":"m","source":"9–9 / 9A–9A","status":"documentada / separación por material"}],"geometry":[{"label":"Extensión de la malla en X","value":6.206609,"unit":"m","source":"Geometría releída del IFC; datum absoluto de proceso provisional","status":"derivado"},{"label":"Extensión de la malla en Y","value":1.2420990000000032,"unit":"m","source":"Geometría releída del IFC; datum absoluto de proceso provisional","status":"derivado"},{"label":"Extensión de la malla en Z","value":2.2,"unit":"m","source":"Geometría releída del IFC; datum absoluto de proceso provisional","status":"derivado"},{"label":"Cota inferior de visualización","value":284.9,"unit":"m","source":"Geometría releída del IFC; datum absoluto de proceso provisional","status":"derivado"},{"label":"Cota superior de visualización","value":287.1,"unit":"m","source":"Geometría releída del IFC; datum absoluto de proceso provisional","status":"derivado"}]} | {"documentId":"LHD2609-JG00100-20260904","title":"Cimentaciones de equipos y pedestales del fabricante · revisión recibida 04/09/2026","date":"2026-09-04","sheet":"9–9 / 9A–9A","fileName":"LHD2609-JG00100_20260904.dwg","revisionCaveat":"Fecha de revisión tomada del nombre recibido; cajetines internos mantienen 02/07/2026 y algunos textos de plantilla.","sourceFileSha256":"b42eb027b7bc0b14c38d1d13514f4899b58a732aa8d0ba2ccf10fa2fc3192890"} | provisional | ["Planta: −2,200 m. Secciones: fondo −2,000 m, losa superior −1,200 m; se adoptan secciones.","La última línea transversal presenta una discrepancia de 4 mm respecto a los ejes de pilares; se conserva la posición de cada contorno fuente."] | {"Cota inferior relativa (m)":-1.2,"Cota superior relativa (m)":1,"Cero absoluto de visualización (m)":286.1,"Estado del cero absoluto":"Provisional","Criterio":"Las cotas relativas proceden del dibujo; la equivalencia absoluta no está confirmada."} | {"boundingBoxM":{"min":[35.947841,44.001582,-0.1],"max":[42.15445,45.243681,2.1]},"extentsM":[6.206609,1.242099,2.2],"meshSurfaceM2":34.052002,"meshVolumeM3":5.464801,"closedSolid":true,"basis":"Magnitudes de las mallas representadas, no cantidades certificadas de obra, compra o fabricación. Las partes pueden compartir superficies; no se suman como un despiece de materiales."} | {"profileId":"concrete_reinforced","name":"Hormigón armado · gris natural","materialName":"Hormigón armado · clase pendiente de confirmar","physicalMaterialStatus":"Clase no confirmada en la hoja de equipo","physicalMaterialSource":"Geometría de cimentación del fabricante; no se extrapola HA-30 de la nota de pedestales.","appearanceStatus":"criterio_visual","appearanceBasis":"Interpretación visual del material documental; el acabado, tono y parámetros PBR no son una especificación contractual.","note":"La apariencia gráfica no modifica ni confirma la especificación física del material."} | {"elementId":"found_0904_025c0b3a525bba","ifcGuid":"2TaELbY0HSleGqS6LlVZDn","ifcClass":"IfcFooting","buildingId":"process_plant","buildingName":"Zona de separación de aire","sourceDocumentId":"LHD2609-JG00100-20260904","sourceRepresentationKind":"foundation"} | {"layerId":"foundations","layerName":"Cimentaciones","role":"Cimentación industrial","basis":"Clasificación por función del elemento; no modifica las especificaciones documentales."} | {"profileId":"concrete_reinforced","name":"Hormigón armado · gris natural","status":"criterio_visual","basis":"Interpretación visual del material documental; el acabado, tono y parámetros PBR no son una especificación contractual.","physicalMaterialUnchanged":true} | 5.4648 | Hormigón armado · clase pendiente de confirmar | Hormigón armado · gris natural | found_0904_025c0b3a525bba | Geometría de cimentación del fabricante; no se extrapola HA-30 de la nota de pedestales. | Clase no confirmada en la hoja de equipo | concrete_reinforced | [0.666667,0.662745,0.619608] | 0.96 | Zona de separación de aire; BIM · Cimentaciones | 6.20661 | 1.2421 | 2.2 | 284.9 | 287.1 | F-WT3001 | ["WT3001A","WT3001B","WT3001C","WT3001D"] | [] | 9–9 / 9A–9A | ["25DC/25E1","25DC/25E2","25DC/25E4","25DC/2604","25DC/25E5","2473E"] | F-WT3001/Cimentación común de torres de refrigeración · murete transversal 4 | foundation | Geometría de fabricante; implantación absoluta provisional | WT3001A, WT3001B, WT3001C, WT3001D | Cimentaciones de equipos y pedestales del fabricante · revisión recibida 04/09/2026 | 25DC/25E1, 25DC/25E2, 25DC/25E4, 25DC/2604, 25DC/25E5, 2473E | -1.2 | 1 | 2.484 | Cotas relativas del dibujo. La equivalencia con un datum absoluto está pendiente. | Z del modelo = cota relativa + 1,10 m. Correspondencia provisional con 286,10 m; no es cota de obra confirmada. | Sección y contornos del fabricante; incidencias conservadas | 6.21 | 0.4 | Planta: −2,200 m. Secciones: fondo −2,000 m, losa superior −1,200 m; se adoptan secciones. / La última línea transversal presenta una discrepancia de 4 mm respecto a los ejes de pilares; se conserva la posición de cada contorno fuente.
Cimentación común de torres de refrigeración · murete transversal 5 | Parcela industrial Jinhong | Cimentación industrial | Cimentaciones de equipos y pedestales del fabricante · revisión recibida 04/09/2026 | 6.20661 | 1.2421 | 2.2 | 34.052 | 5.4648 | process_plant | Zona de separación de aire | {"name":"Hormigón armado · clase pendiente de confirmar","status":"Clase no confirmada en la hoja de equipo","source":"Geometría de cimentación del fabricante; no se extrapola HA-30 de la nota de pedestales."} | {"documented":[{"label":"Extensión local X","value":6.21,"unit":"m","source":"25DC/25E1, 25DC/25E2, 25DC/25E4, 25DC/2604, 25DC/25E5, 2473E","status":"derivada del contorno CAD"},{"label":"Extensión local Y","value":0.4,"unit":"m","source":"25DC/25E1, 25DC/25E2, 25DC/25E4, 25DC/2604, 25DC/25E5, 2473E","status":"derivada del contorno CAD"},{"label":"Cota inferior relativa adoptada","value":-1.2,"unit":"m","source":"9–9 / 9A–9A","status":"interpretación con conflicto conservado"},{"label":"Cota superior relativa adoptada","value":1,"unit":"m","source":"9–9 / 9A–9A","status":"documentada / separación por material"}],"geometry":[{"label":"Extensión de la malla en X","value":6.206609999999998,"unit":"m","source":"Geometría releída del IFC; datum absoluto de proceso provisional","status":"derivado"},{"label":"Extensión de la malla en Y","value":1.2420990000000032,"unit":"m","source":"Geometría releída del IFC; datum absoluto de proceso provisional","status":"derivado"},{"label":"Extensión de la malla en Z","value":2.2,"unit":"m","source":"Geometría releída del IFC; datum absoluto de proceso provisional","status":"derivado"},{"label":"Cota inferior de visualización","value":284.9,"unit":"m","source":"Geometría releída del IFC; datum absoluto de proceso provisional","status":"derivado"},{"label":"Cota superior de visualización","value":287.1,"unit":"m","source":"Geometría releída del IFC; datum absoluto de proceso provisional","status":"derivado"}]} | {"documentId":"LHD2609-JG00100-20260904","title":"Cimentaciones de equipos y pedestales del fabricante · revisión recibida 04/09/2026","date":"2026-09-04","sheet":"9–9 / 9A–9A","fileName":"LHD2609-JG00100_20260904.dwg","revisionCaveat":"Fecha de revisión tomada del nombre recibido; cajetines internos mantienen 02/07/2026 y algunos textos de plantilla.","sourceFileSha256":"b42eb027b7bc0b14c38d1d13514f4899b58a732aa8d0ba2ccf10fa2fc3192890"} | provisional | ["Planta: −2,200 m. Secciones: fondo −2,000 m, losa superior −1,200 m; se adoptan secciones.","La última línea transversal presenta una discrepancia de 4 mm respecto a los ejes de pilares; se conserva la posición de cada contorno fuente."] | {"Cota inferior relativa (m)":-1.2,"Cota superior relativa (m)":1,"Cero absoluto de visualización (m)":286.1,"Estado del cero absoluto":"Provisional","Criterio":"Las cotas relativas proceden del dibujo; la equivalencia absoluta no está confirmada."} | {"boundingBoxM":{"min":[35.655819,41.877562,-0.1],"max":[41.862429,43.119661,2.1]},"extentsM":[6.20661,1.242099,2.2],"meshSurfaceM2":34.052004,"meshVolumeM3":5.464803,"closedSolid":true,"basis":"Magnitudes de las mallas representadas, no cantidades certificadas de obra, compra o fabricación. Las partes pueden compartir superficies; no se suman como un despiece de materiales."} | {"profileId":"concrete_reinforced","name":"Hormigón armado · gris natural","materialName":"Hormigón armado · clase pendiente de confirmar","physicalMaterialStatus":"Clase no confirmada en la hoja de equipo","physicalMaterialSource":"Geometría de cimentación del fabricante; no se extrapola HA-30 de la nota de pedestales.","appearanceStatus":"criterio_visual","appearanceBasis":"Interpretación visual del material documental; el acabado, tono y parámetros PBR no son una especificación contractual.","note":"La apariencia gráfica no modifica ni confirma la especificación física del material."} | {"elementId":"found_0904_32a7bac0d6ed13","ifcGuid":"2IVar4nMvOK9Dr23s9cIUl","ifcClass":"IfcFooting","buildingId":"process_plant","buildingName":"Zona de separación de aire","sourceDocumentId":"LHD2609-JG00100-20260904","sourceRepresentationKind":"foundation"} | {"layerId":"foundations","layerName":"Cimentaciones","role":"Cimentación industrial","basis":"Clasificación por función del elemento; no modifica las especificaciones documentales."} | {"profileId":"concrete_reinforced","name":"Hormigón armado · gris natural","status":"criterio_visual","basis":"Interpretación visual del material documental; el acabado, tono y parámetros PBR no son una especificación contractual.","physicalMaterialUnchanged":true} | 5.4648 | Hormigón armado · clase pendiente de confirmar | Hormigón armado · gris natural | found_0904_32a7bac0d6ed13 | Geometría de cimentación del fabricante; no se extrapola HA-30 de la nota de pedestales. | Clase no confirmada en la hoja de equipo | concrete_reinforced | [0.666667,0.662745,0.619608] | 0.96 | Zona de separación de aire; BIM · Cimentaciones | 6.20661 | 1.2421 | 2.2 | 284.9 | 287.1 | F-WT3001 | ["WT3001A","WT3001B","WT3001C","WT3001D"] | [] | 9–9 / 9A–9A | ["25DC/25E1","25DC/25E2","25DC/25E4","25DC/2604","25DC/25E5","2473E"] | F-WT3001/Cimentación común de torres de refrigeración · murete transversal 5 | foundation | Geometría de fabricante; implantación absoluta provisional | WT3001A, WT3001B, WT3001C, WT3001D | Cimentaciones de equipos y pedestales del fabricante · revisión recibida 04/09/2026 | 25DC/25E1, 25DC/25E2, 25DC/25E4, 25DC/2604, 25DC/25E5, 2473E | -1.2 | 1 | 2.484 | Cotas relativas del dibujo. La equivalencia con un datum absoluto está pendiente. | Z del modelo = cota relativa + 1,10 m. Correspondencia provisional con 286,10 m; no es cota de obra confirmada. | Sección y contornos del fabricante; incidencias conservadas | 6.21 | 0.4 | Planta: −2,200 m. Secciones: fondo −2,000 m, losa superior −1,200 m; se adoptan secciones. / La última línea transversal presenta una discrepancia de 4 mm respecto a los ejes de pilares; se conserva la posición de cada contorno fuente.
Cimentación común de torres de refrigeración · pilar DZ9 01 | Parcela industrial Jinhong | Cimentación industrial | Cimentaciones de equipos y pedestales del fabricante · revisión recibida 04/09/2026 | 0.450754 | 0.450754 | 1 | 1.92 | 0.16 | process_plant | Zona de separación de aire | {"name":"Hormigón armado · clase pendiente de confirmar","status":"Clase no confirmada en la hoja de equipo","source":"Geometría de cimentación del fabricante; no se extrapola HA-30 de la nota de pedestales."} | {"documented":[{"label":"Extensión local X","value":0.4,"unit":"m","source":"25DC/25E1, 25DC/25E2, 25DC/25E4, 25DC/2604, 25DC/25E5, 2473E","status":"derivada del contorno CAD"},{"label":"Extensión local Y","value":0.4,"unit":"m","source":"25DC/25E1, 25DC/25E2, 25DC/25E4, 25DC/2604, 25DC/25E5, 2473E","status":"derivada del contorno CAD"},{"label":"Cota inferior relativa adoptada","value":1,"unit":"m","source":"9–9 / 9A–9A","status":"interpretación con conflicto conservado"},{"label":"Cota superior relativa adoptada","value":2,"unit":"m","source":"9–9 / 9A–9A","status":"documentada / separación por material"}],"geometry":[{"label":"Extensión de la malla en X","value":0.4507539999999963,"unit":"m","source":"Geometría releída del IFC; datum absoluto de proceso provisional","status":"derivado"},{"label":"Extensión de la malla en Y","value":0.45075400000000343,"unit":"m","source":"Geometría releída del IFC; datum absoluto de proceso provisional","status":"derivado"},{"label":"Extensión de la malla en Z","value":1.0,"unit":"m","source":"Geometría releída del IFC; datum absoluto de proceso provisional","status":"derivado"},{"label":"Cota inferior de visualización","value":287.1,"unit":"m","source":"Geometría releída del IFC; datum absoluto de proceso provisional","status":"derivado"},{"label":"Cota superior de visualización","value":288.1,"unit":"m","source":"Geometría releída del IFC; datum absoluto de proceso provisional","status":"derivado"}]} | {"documentId":"LHD2609-JG00100-20260904","title":"Cimentaciones de equipos y pedestales del fabricante · revisión recibida 04/09/2026","date":"2026-09-04","sheet":"9–9 / 9A–9A","fileName":"LHD2609-JG00100_20260904.dwg","revisionCaveat":"Fecha de revisión tomada del nombre recibido; cajetines internos mantienen 02/07/2026 y algunos textos de plantilla.","sourceFileSha256":"b42eb027b7bc0b14c38d1d13514f4899b58a732aa8d0ba2ccf10fa2fc3192890"} | provisional | ["Planta: −2,200 m. Secciones: fondo −2,000 m, losa superior −1,200 m; se adoptan secciones.","La última línea transversal presenta una discrepancia de 4 mm respecto a los ejes de pilares; se conserva la posición de cada contorno fuente."] | {"Cota inferior relativa (m)":1,"Cota superior relativa (m)":2,"Cero absoluto de visualización (m)":286.1,"Estado del cero absoluto":"Provisional","Criterio":"Las cotas relativas proceden del dibujo; la equivalencia absoluta no está confirmada."} | {"boundingBoxM":{"min":[36.82227,51.153098,2.1],"max":[37.273024,51.603852,3.1]},"extentsM":[0.450754,0.450754,1.0],"meshSurfaceM2":1.920001,"meshVolumeM3":0.16,"closedSolid":true,"basis":"Magnitudes de las mallas representadas, no cantidades certificadas de obra, compra o fabricación. Las partes pueden compartir superficies; no se suman como un despiece de materiales."} | {"profileId":"concrete_reinforced","name":"Hormigón armado · gris natural","materialName":"Hormigón armado · clase pendiente de confirmar","physicalMaterialStatus":"Clase no confirmada en la hoja de equipo","physicalMaterialSource":"Geometría de cimentación del fabricante; no se extrapola HA-30 de la nota de pedestales.","appearanceStatus":"criterio_visual","appearanceBasis":"Interpretación visual del material documental; el acabado, tono y parámetros PBR no son una especificación contractual.","note":"La apariencia gráfica no modifica ni confirma la especificación física del material."} | {"elementId":"found_0904_8f22db24747aea","ifcGuid":"2akjb3QDbQEu0FLvrWN67V","ifcClass":"IfcFooting","buildingId":"process_plant","buildingName":"Zona de separación de aire","sourceDocumentId":"LHD2609-JG00100-20260904","sourceRepresentationKind":"foundation"} | {"layerId":"foundations","layerName":"Cimentaciones","role":"Cimentación industrial","basis":"Clasificación por función del elemento; no modifica las especificaciones documentales."} | {"profileId":"concrete_reinforced","name":"Hormigón armado · gris natural","status":"criterio_visual","basis":"Interpretación visual del material documental; el acabado, tono y parámetros PBR no son una especificación contractual.","physicalMaterialUnchanged":true} | 0.16 | Hormigón armado · clase pendiente de confirmar | Hormigón armado · gris natural | found_0904_8f22db24747aea | Geometría de cimentación del fabricante; no se extrapola HA-30 de la nota de pedestales. | Clase no confirmada en la hoja de equipo | concrete_reinforced | [0.666667,0.662745,0.619608] | 0.96 | Zona de separación de aire; BIM · Cimentaciones | 0.450754 | 0.450754 | 1 | 287.1 | 288.1 | F-WT3001 | ["WT3001A","WT3001B","WT3001C","WT3001D"] | [] | 9–9 / 9A–9A | ["25DC/25E1","25DC/25E2","25DC/25E4","25DC/2604","25DC/25E5","2473E"] | F-WT3001/Cimentación común de torres de refrigeración · pilar DZ9 01 | foundation | Geometría de fabricante; implantación absoluta provisional | WT3001A, WT3001B, WT3001C, WT3001D | Cimentaciones de equipos y pedestales del fabricante · revisión recibida 04/09/2026 | 25DC/25E1, 25DC/25E2, 25DC/25E4, 25DC/2604, 25DC/25E5, 2473E | 1 | 2 | 0.16 | Cotas relativas del dibujo. La equivalencia con un datum absoluto está pendiente. | Z del modelo = cota relativa + 1,10 m. Correspondencia provisional con 286,10 m; no es cota de obra confirmada. | Sección y contornos del fabricante; incidencias conservadas | 0.4 | 0.4 | Planta: −2,200 m. Secciones: fondo −2,000 m, losa superior −1,200 m; se adoptan secciones. / La última línea transversal presenta una discrepancia de 4 mm respecto a los ejes de pilares; se conserva la posición de cada contorno fuente.
Cimentación común de torres de refrigeración · pilar DZ9 02 | Parcela industrial Jinhong | Cimentación industrial | Cimentaciones de equipos y pedestales del fabricante · revisión recibida 04/09/2026 | 0.450754 | 0.450754 | 1 | 1.92 | 0.16 | process_plant | Zona de separación de aire | {"name":"Hormigón armado · clase pendiente de confirmar","status":"Clase no confirmada en la hoja de equipo","source":"Geometría de cimentación del fabricante; no se extrapola HA-30 de la nota de pedestales."} | {"documented":[{"label":"Extensión local X","value":0.4,"unit":"m","source":"25DC/25E1, 25DC/25E2, 25DC/25E4, 25DC/2604, 25DC/25E5, 2473E","status":"derivada del contorno CAD"},{"label":"Extensión local Y","value":0.4,"unit":"m","source":"25DC/25E1, 25DC/25E2, 25DC/25E4, 25DC/2604, 25DC/25E5, 2473E","status":"derivada del contorno CAD"},{"label":"Cota inferior relativa adoptada","value":1,"unit":"m","source":"9–9 / 9A–9A","status":"interpretación con conflicto conservado"},{"label":"Cota superior relativa adoptada","value":2,"unit":"m","source":"9–9 / 9A–9A","status":"documentada / separación por material"}],"geometry":[{"label":"Extensión de la malla en X","value":0.45075400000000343,"unit":"m","source":"Geometría releída del IFC; datum absoluto de proceso provisional","status":"derivado"},{"label":"Extensión de la malla en Y","value":0.45075400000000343,"unit":"m","source":"Geometría releída del IFC; datum absoluto de proceso provisional","status":"derivado"},{"label":"Extensión de la malla en Z","value":1.0,"unit":"m","source":"Geometría releída del IFC; datum absoluto de proceso provisional","status":"derivado"},{"label":"Cota inferior de visualización","value":287.1,"unit":"m","source":"Geometría releída del IFC; datum absoluto de proceso provisional","status":"derivado"},{"label":"Cota superior de visualización","value":288.1,"unit":"m","source":"Geometría releída del IFC; datum absoluto de proceso provisional","status":"derivado"}]} | {"documentId":"LHD2609-JG00100-20260904","title":"Cimentaciones de equipos y pedestales del fabricante · revisión recibida 04/09/2026","date":"2026-09-04","sheet":"9–9 / 9A–9A","fileName":"LHD2609-JG00100_20260904.dwg","revisionCaveat":"Fecha de revisión tomada del nombre recibido; cajetines internos mantienen 02/07/2026 y algunos textos de plantilla.","sourceFileSha256":"b42eb027b7bc0b14c38d1d13514f4899b58a732aa8d0ba2ccf10fa2fc3192890"} | provisional | ["Planta: −2,200 m. Secciones: fondo −2,000 m, losa superior −1,200 m; se adoptan secciones.","La última línea transversal presenta una discrepancia de 4 mm respecto a los ejes de pilares; se conserva la posición de cada contorno fuente."] | {"Cota inferior relativa (m)":1,"Cota superior relativa (m)":2,"Cero absoluto de visualización (m)":286.1,"Estado del cero absoluto":"Provisional","Criterio":"Las cotas relativas proceden del dibujo; la equivalencia absoluta no está confirmada."} | {"boundingBoxM":{"min":[37.926879,51.00123,2.1],"max":[38.377633,51.451984,3.1]},"extentsM":[0.450754,0.450754,1.0],"meshSurfaceM2":1.92,"meshVolumeM3":0.16,"closedSolid":true,"basis":"Magnitudes de las mallas representadas, no cantidades certificadas de obra, compra o fabricación. Las partes pueden compartir superficies; no se suman como un despiece de materiales."} | {"profileId":"concrete_reinforced","name":"Hormigón armado · gris natural","materialName":"Hormigón armado · clase pendiente de confirmar","physicalMaterialStatus":"Clase no confirmada en la hoja de equipo","physicalMaterialSource":"Geometría de cimentación del fabricante; no se extrapola HA-30 de la nota de pedestales.","appearanceStatus":"criterio_visual","appearanceBasis":"Interpretación visual del material documental; el acabado, tono y parámetros PBR no son una especificación contractual.","note":"La apariencia gráfica no modifica ni confirma la especificación física del material."} | {"elementId":"found_0904_0722d46dd10b31","ifcGuid":"35SA7YaKnSUPGzijdBE7l6","ifcClass":"IfcFooting","buildingId":"process_plant","buildingName":"Zona de separación de aire","sourceDocumentId":"LHD2609-JG00100-20260904","sourceRepresentationKind":"foundation"} | {"layerId":"foundations","layerName":"Cimentaciones","role":"Cimentación industrial","basis":"Clasificación por función del elemento; no modifica las especificaciones documentales."} | {"profileId":"concrete_reinforced","name":"Hormigón armado · gris natural","status":"criterio_visual","basis":"Interpretación visual del material documental; el acabado, tono y parámetros PBR no son una especificación contractual.","physicalMaterialUnchanged":true} | 0.16 | Hormigón armado · clase pendiente de confirmar | Hormigón armado · gris natural | found_0904_0722d46dd10b31 | Geometría de cimentación del fabricante; no se extrapola HA-30 de la nota de pedestales. | Clase no confirmada en la hoja de equipo | concrete_reinforced | [0.666667,0.662745,0.619608] | 0.96 | Zona de separación de aire; BIM · Cimentaciones | 0.450754 | 0.450754 | 1 | 287.1 | 288.1 | F-WT3001 | ["WT3001A","WT3001B","WT3001C","WT3001D"] | [] | 9–9 / 9A–9A | ["25DC/25E1","25DC/25E2","25DC/25E4","25DC/2604","25DC/25E5","2473E"] | F-WT3001/Cimentación común de torres de refrigeración · pilar DZ9 02 | foundation | Geometría de fabricante; implantación absoluta provisional | WT3001A, WT3001B, WT3001C, WT3001D | Cimentaciones de equipos y pedestales del fabricante · revisión recibida 04/09/2026 | 25DC/25E1, 25DC/25E2, 25DC/25E4, 25DC/2604, 25DC/25E5, 2473E | 1 | 2 | 0.16 | Cotas relativas del dibujo. La equivalencia con un datum absoluto está pendiente. | Z del modelo = cota relativa + 1,10 m. Correspondencia provisional con 286,10 m; no es cota de obra confirmada. | Sección y contornos del fabricante; incidencias conservadas | 0.4 | 0.4 | Planta: −2,200 m. Secciones: fondo −2,000 m, losa superior −1,200 m; se adoptan secciones. / La última línea transversal presenta una discrepancia de 4 mm respecto a los ejes de pilares; se conserva la posición de cada contorno fuente.
Cimentación común de torres de refrigeración · pilar DZ9 03 | Parcela industrial Jinhong | Cimentación industrial | Cimentaciones de equipos y pedestales del fabricante · revisión recibida 04/09/2026 | 0.450753 | 0.450754 | 1 | 1.92 | 0.16 | process_plant | Zona de separación de aire | {"name":"Hormigón armado · clase pendiente de confirmar","status":"Clase no confirmada en la hoja de equipo","source":"Geometría de cimentación del fabricante; no se extrapola HA-30 de la nota de pedestales."} | {"documented":[{"label":"Extensión local X","value":0.4,"unit":"m","source":"25DC/25E1, 25DC/25E2, 25DC/25E4, 25DC/2604, 25DC/25E5, 2473E","status":"derivada del contorno CAD"},{"label":"Extensión local Y","value":0.4,"unit":"m","source":"25DC/25E1, 25DC/25E2, 25DC/25E4, 25DC/2604, 25DC/25E5, 2473E","status":"derivada del contorno CAD"},{"label":"Cota inferior relativa adoptada","value":1,"unit":"m","source":"9–9 / 9A–9A","status":"interpretación con conflicto conservado"},{"label":"Cota superior relativa adoptada","value":2,"unit":"m","source":"9–9 / 9A–9A","status":"documentada / separación por material"}],"geometry":[{"label":"Extensión de la malla en X","value":0.45075299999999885,"unit":"m","source":"Geometría releída del IFC; datum absoluto de proceso provisional","status":"derivado"},{"label":"Extensión de la malla en Y","value":0.4507539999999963,"unit":"m","source":"Geometría releída del IFC; datum absoluto de proceso provisional","status":"derivado"},{"label":"Extensión de la malla en Z","value":1.0,"unit":"m","source":"Geometría releída del IFC; datum absoluto de proceso provisional","status":"derivado"},{"label":"Cota inferior de visualización","value":287.1,"unit":"m","source":"Geometría releída del IFC; datum absoluto de proceso provisional","status":"derivado"},{"label":"Cota superior de visualización","value":288.1,"unit":"m","source":"Geometría releída del IFC; datum absoluto de proceso provisional","status":"derivado"}]} | {"documentId":"LHD2609-JG00100-20260904","title":"Cimentaciones de equipos y pedestales del fabricante · revisión recibida 04/09/2026","date":"2026-09-04","sheet":"9–9 / 9A–9A","fileName":"LHD2609-JG00100_20260904.dwg","revisionCaveat":"Fecha de revisión tomada del nombre recibido; cajetines internos mantienen 02/07/2026 y algunos textos de plantilla.","sourceFileSha256":"b42eb027b7bc0b14c38d1d13514f4899b58a732aa8d0ba2ccf10fa2fc3192890"} | provisional | ["Planta: −2,200 m. Secciones: fondo −2,000 m, losa superior −1,200 m; se adoptan secciones.","La última línea transversal presenta una discrepancia de 4 mm respecto a los ejes de pilares; se conserva la posición de cada contorno fuente."] | {"Cota inferior relativa (m)":1,"Cota superior relativa (m)":2,"Cero absoluto de visualización (m)":286.1,"Estado del cero absoluto":"Provisional","Criterio":"Las cotas relativas proceden del dibujo; la equivalencia absoluta no está confirmada."} | {"boundingBoxM":{"min":[38.741219,50.889271,2.1],"max":[39.191972,51.340025,3.1]},"extentsM":[0.450753,0.450754,1.0],"meshSurfaceM2":1.919999,"meshVolumeM3":0.16,"closedSolid":true,"basis":"Magnitudes de las mallas representadas, no cantidades certificadas de obra, compra o fabricación. Las partes pueden compartir superficies; no se suman como un despiece de materiales."} | {"profileId":"concrete_reinforced","name":"Hormigón armado · gris natural","materialName":"Hormigón armado · clase pendiente de confirmar","physicalMaterialStatus":"Clase no confirmada en la hoja de equipo","physicalMaterialSource":"Geometría de cimentación del fabricante; no se extrapola HA-30 de la nota de pedestales.","appearanceStatus":"criterio_visual","appearanceBasis":"Interpretación visual del material documental; el acabado, tono y parámetros PBR no son una especificación contractual.","note":"La apariencia gráfica no modifica ni confirma la especificación física del material."} | {"elementId":"found_0904_9c35a87f90e679","ifcGuid":"31PvOtWVHNJQVaYb6cMiPH","ifcClass":"IfcFooting","buildingId":"process_plant","buildingName":"Zona de separación de aire","sourceDocumentId":"LHD2609-JG00100-20260904","sourceRepresentationKind":"foundation"} | {"layerId":"foundations","layerName":"Cimentaciones","role":"Cimentación industrial","basis":"Clasificación por función del elemento; no modifica las especificaciones documentales."} | {"profileId":"concrete_reinforced","name":"Hormigón armado · gris natural","status":"criterio_visual","basis":"Interpretación visual del material documental; el acabado, tono y parámetros PBR no son una especificación contractual.","physicalMaterialUnchanged":true} | 0.16 | Hormigón armado · clase pendiente de confirmar | Hormigón armado · gris natural | found_0904_9c35a87f90e679 | Geometría de cimentación del fabricante; no se extrapola HA-30 de la nota de pedestales. | Clase no confirmada en la hoja de equipo | concrete_reinforced | [0.666667,0.662745,0.619608] | 0.96 | Zona de separación de aire; BIM · Cimentaciones | 0.450753 | 0.450754 | 1 | 287.1 | 288.1 | F-WT3001 | ["WT3001A","WT3001B","WT3001C","WT3001D"] | [] | 9–9 / 9A–9A | ["25DC/25E1","25DC/25E2","25DC/25E4","25DC/2604","25DC/25E5","2473E"] | F-WT3001/Cimentación común de torres de refrigeración · pilar DZ9 03 | foundation | Geometría de fabricante; implantación absoluta provisional | WT3001A, WT3001B, WT3001C, WT3001D | Cimentaciones de equipos y pedestales del fabricante · revisión recibida 04/09/2026 | 25DC/25E1, 25DC/25E2, 25DC/25E4, 25DC/2604, 25DC/25E5, 2473E | 1 | 2 | 0.16 | Cotas relativas del dibujo. La equivalencia con un datum absoluto está pendiente. | Z del modelo = cota relativa + 1,10 m. Correspondencia provisional con 286,10 m; no es cota de obra confirmada. | Sección y contornos del fabricante; incidencias conservadas | 0.4 | 0.4 | Planta: −2,200 m. Secciones: fondo −2,000 m, losa superior −1,200 m; se adoptan secciones. / La última línea transversal presenta una discrepancia de 4 mm respecto a los ejes de pilares; se conserva la posición de cada contorno fuente.
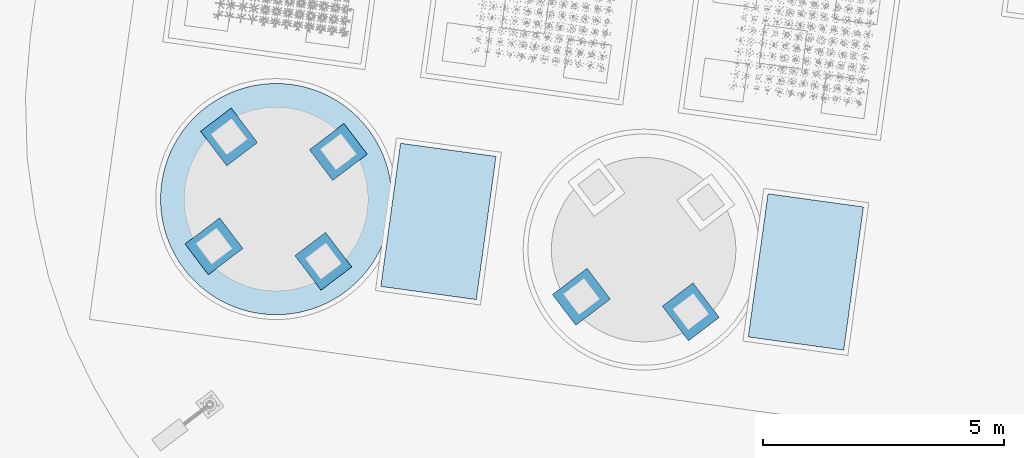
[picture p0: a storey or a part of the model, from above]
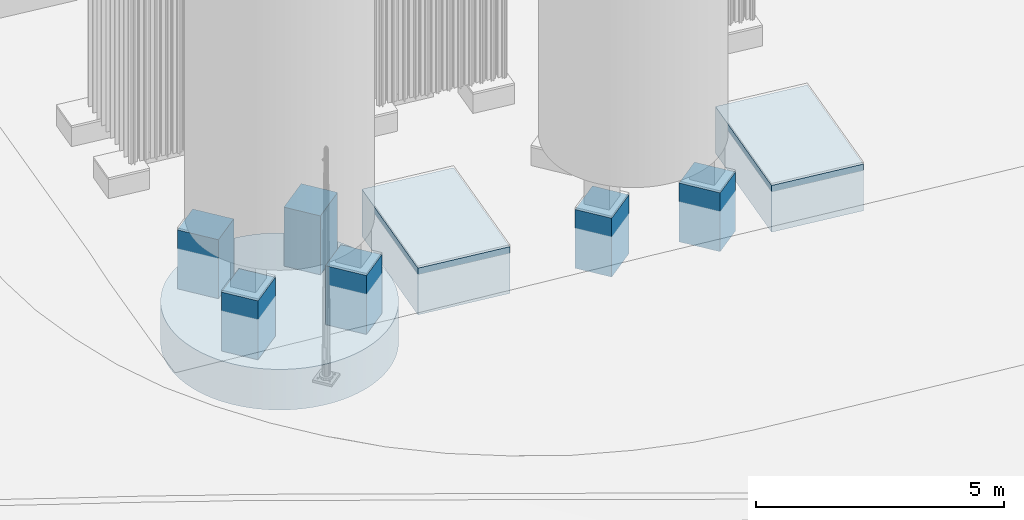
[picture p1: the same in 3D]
Properties of the parts of a building model (IFC4), part 71 of 134

# IfcFooting (214)
Name | In | Description = category = Categoria = Funcion | Document | ExtensionX (m) | ExtensionY (m) | ExtensionZ (m) | SuperficieDeLaMalla (m2) | VolumenGeometrico (m3) | buildingId | buildingName | material | dimensions | JH_InformacionBIM, source = DocumentoFuente | JH_InformacionBIM, status = EstadoDeInformacion | issues = IncidenciasPendientes | positioning = PosicionYEstado | geometryMetrics | materialAppearance | visualizationIdentity | classification | appearance | Volumen geométrico (m³) | JH_Trazabilidad, Material = name | Acabado de visualización = Acabado | Identificador | JH_EvidenciaDeMaterial, source | JH_EvidenciaDeMaterial, status | Perfil | ColorRGB | Rugosidad | Group | Extensión de la malla en X (m) | Extensión de la malla en Y (m) | Extensión de la malla en Z (m) = Espesor o altura real de sección (m) | Cota inferior de visualización (m) | Cota superior de visualización (m) | assemblyId = Conjunto de cimentación | equipmentIds | supportPositionIds | sectionRef = Sección de referencia | sourceCadHandles | stableElementKey | representationKind | geometryStatus | Equipos asociados | Documento de origen | Identificadores CAD de referencia | Cota inferior relativa (m) = Cota inferior relativa adoptada (m) | Cota superior relativa (m) = Cota superior relativa adoptada (m) | Área de planta (m²) | Referencia vertical | Implantación para visualización | Estado de la geometría | Extensión local X (m) | Extensión local Y (m) | Incidencias de origen
Cimentación común de torres de refrigeración · pilar DZ9 04 | Parcela industrial Jinhong | Cimentación industrial | Cimentaciones de equipos y pedestales del fabricante · revisión recibida 04/09/2026 | 0.450754 | 0.450754 | 1 | 1.92 | 0.16 | process_plant | Zona de separación de aire | {"name":"Hormigón armado · clase pendiente de confirmar","status":"Clase no confirmada en la hoja de equipo","source":"Geometría de cimentación del fabricante; no se extrapola HA-30 de la nota de pedestales."} | {"documented":[{"label":"Extensión local X","value":0.4,"unit":"m","source":"25DC/25E1, 25DC/25E2, 25DC/25E4, 25DC/2604, 25DC/25E5, 2473E","status":"derivada del contorno CAD"},{"label":"Extensión local Y","value":0.4,"unit":"m","source":"25DC/25E1, 25DC/25E2, 25DC/25E4, 25DC/2604, 25DC/25E5, 2473E","status":"derivada del contorno CAD"},{"label":"Cota inferior relativa adoptada","value":1,"unit":"m","source":"9–9 / 9A–9A","status":"interpretación con conflicto conservado"},{"label":"Cota superior relativa adoptada","value":2,"unit":"m","source":"9–9 / 9A–9A","status":"documentada / separación por material"}],"geometry":[{"label":"Extensión de la malla en X","value":0.45075400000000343,"unit":"m","source":"Geometría releída del IFC; datum absoluto de proceso provisional","status":"derivado"},{"label":"Extensión de la malla en Y","value":0.45075400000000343,"unit":"m","source":"Geometría releída del IFC; datum absoluto de proceso provisional","status":"derivado"},{"label":"Extensión de la malla en Z","value":1.0,"unit":"m","source":"Geometría releída del IFC; datum absoluto de proceso provisional","status":"derivado"},{"label":"Cota inferior de visualización","value":287.1,"unit":"m","source":"Geometría releída del IFC; datum absoluto de proceso provisional","status":"derivado"},{"label":"Cota superior de visualización","value":288.1,"unit":"m","source":"Geometría releída del IFC; datum absoluto de proceso provisional","status":"derivado"}]} | {"documentId":"LHD2609-JG00100-20260904","title":"Cimentaciones de equipos y pedestales del fabricante · revisión recibida 04/09/2026","date":"2026-09-04","sheet":"9–9 / 9A–9A","fileName":"LHD2609-JG00100_20260904.dwg","revisionCaveat":"Fecha de revisión tomada del nombre recibido; cajetines internos mantienen 02/07/2026 y algunos textos de plantilla.","sourceFileSha256":"b42eb027b7bc0b14c38d1d13514f4899b58a732aa8d0ba2ccf10fa2fc3192890"} | provisional | ["Planta: −2,200 m. Secciones: fondo −2,000 m, losa superior −1,200 m; se adoptan secciones.","La última línea transversal presenta una discrepancia de 4 mm respecto a los ejes de pilares; se conserva la posición de cada contorno fuente."] | {"Cota inferior relativa (m)":1,"Cota superior relativa (m)":2,"Cero absoluto de visualización (m)":286.1,"Estado del cero absoluto":"Provisional","Criterio":"Las cotas relativas proceden del dibujo; la equivalencia absoluta no está confirmada."} | {"boundingBoxM":{"min":[40.659177,50.62558,2.1],"max":[41.109931,51.076334,3.1]},"extentsM":[0.450754,0.450754,1.0],"meshSurfaceM2":1.920001,"meshVolumeM3":0.16,"closedSolid":true,"basis":"Magnitudes de las mallas representadas, no cantidades certificadas de obra, compra o fabricación. Las partes pueden compartir superficies; no se suman como un despiece de materiales."} | {"profileId":"concrete_reinforced","name":"Hormigón armado · gris natural","materialName":"Hormigón armado · clase pendiente de confirmar","physicalMaterialStatus":"Clase no confirmada en la hoja de equipo","physicalMaterialSource":"Geometría de cimentación del fabricante; no se extrapola HA-30 de la nota de pedestales.","appearanceStatus":"criterio_visual","appearanceBasis":"Interpretación visual del material documental; el acabado, tono y parámetros PBR no son una especificación contractual.","note":"La apariencia gráfica no modifica ni confirma la especificación física del material."} | {"elementId":"found_0904_fbfbdab013ea73","ifcGuid":"19Wc6J32nPdAw8DCyogKrI","ifcClass":"IfcFooting","buildingId":"process_plant","buildingName":"Zona de separación de aire","sourceDocumentId":"LHD2609-JG00100-20260904","sourceRepresentationKind":"foundation"} | {"layerId":"foundations","layerName":"Cimentaciones","role":"Cimentación industrial","basis":"Clasificación por función del elemento; no modifica las especificaciones documentales."} | {"profileId":"concrete_reinforced","name":"Hormigón armado · gris natural","status":"criterio_visual","basis":"Interpretación visual del material documental; el acabado, tono y parámetros PBR no son una especificación contractual.","physicalMaterialUnchanged":true} | 0.16 | Hormigón armado · clase pendiente de confirmar | Hormigón armado · gris natural | found_0904_fbfbdab013ea73 | Geometría de cimentación del fabricante; no se extrapola HA-30 de la nota de pedestales. | Clase no confirmada en la hoja de equipo | concrete_reinforced | [0.666667,0.662745,0.619608] | 0.96 | Zona de separación de aire; BIM · Cimentaciones | 0.450754 | 0.450754 | 1 | 287.1 | 288.1 | F-WT3001 | ["WT3001A","WT3001B","WT3001C","WT3001D"] | [] | 9–9 / 9A–9A | ["25DC/25E1","25DC/25E2","25DC/25E4","25DC/2604","25DC/25E5","2473E"] | F-WT3001/Cimentación común de torres de refrigeración · pilar DZ9 04 | foundation | Geometría de fabricante; implantación absoluta provisional | WT3001A, WT3001B, WT3001C, WT3001D | Cimentaciones de equipos y pedestales del fabricante · revisión recibida 04/09/2026 | 25DC/25E1, 25DC/25E2, 25DC/25E4, 25DC/2604, 25DC/25E5, 2473E | 1 | 2 | 0.16 | Cotas relativas del dibujo. La equivalencia con un datum absoluto está pendiente. | Z del modelo = cota relativa + 1,10 m. Correspondencia provisional con 286,10 m; no es cota de obra confirmada. | Sección y contornos del fabricante; incidencias conservadas | 0.4 | 0.4 | Planta: −2,200 m. Secciones: fondo −2,000 m, losa superior −1,200 m; se adoptan secciones. / La última línea transversal presenta una discrepancia de 4 mm respecto a los ejes de pilares; se conserva la posición de cada contorno fuente.
Cimentación común de torres de refrigeración · pilar DZ9 05 | Parcela industrial Jinhong | Cimentación industrial | Cimentaciones de equipos y pedestales del fabricante · revisión recibida 04/09/2026 | 0.450754 | 0.450754 | 1 | 1.92 | 0.16 | process_plant | Zona de separación de aire | {"name":"Hormigón armado · clase pendiente de confirmar","status":"Clase no confirmada en la hoja de equipo","source":"Geometría de cimentación del fabricante; no se extrapola HA-30 de la nota de pedestales."} | {"documented":[{"label":"Extensión local X","value":0.4,"unit":"m","source":"25DC/25E1, 25DC/25E2, 25DC/25E4, 25DC/2604, 25DC/25E5, 2473E","status":"derivada del contorno CAD"},{"label":"Extensión local Y","value":0.4,"unit":"m","source":"25DC/25E1, 25DC/25E2, 25DC/25E4, 25DC/2604, 25DC/25E5, 2473E","status":"derivada del contorno CAD"},{"label":"Cota inferior relativa adoptada","value":1,"unit":"m","source":"9–9 / 9A–9A","status":"interpretación con conflicto conservado"},{"label":"Cota superior relativa adoptada","value":2,"unit":"m","source":"9–9 / 9A–9A","status":"documentada / separación por material"}],"geometry":[{"label":"Extensión de la malla en X","value":0.45075400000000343,"unit":"m","source":"Geometría releída del IFC; datum absoluto de proceso provisional","status":"derivado"},{"label":"Extensión de la malla en Y","value":0.4507539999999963,"unit":"m","source":"Geometría releída del IFC; datum absoluto de proceso provisional","status":"derivado"},{"label":"Extensión de la malla en Z","value":1.0,"unit":"m","source":"Geometría releída del IFC; datum absoluto de proceso provisional","status":"derivado"},{"label":"Cota inferior de visualización","value":287.1,"unit":"m","source":"Geometría releída del IFC; datum absoluto de proceso provisional","status":"derivado"},{"label":"Cota superior de visualización","value":288.1,"unit":"m","source":"Geometría releída del IFC; datum absoluto de proceso provisional","status":"derivado"}]} | {"documentId":"LHD2609-JG00100-20260904","title":"Cimentaciones de equipos y pedestales del fabricante · revisión recibida 04/09/2026","date":"2026-09-04","sheet":"9–9 / 9A–9A","fileName":"LHD2609-JG00100_20260904.dwg","revisionCaveat":"Fecha de revisión tomada del nombre recibido; cajetines internos mantienen 02/07/2026 y algunos textos de plantilla.","sourceFileSha256":"b42eb027b7bc0b14c38d1d13514f4899b58a732aa8d0ba2ccf10fa2fc3192890"} | provisional | ["Planta: −2,200 m. Secciones: fondo −2,000 m, losa superior −1,200 m; se adoptan secciones.","La última línea transversal presenta una discrepancia de 4 mm respecto a los ejes de pilares; se conserva la posición de cada contorno fuente."] | {"Cota inferior relativa (m)":1,"Cota superior relativa (m)":2,"Cero absoluto de visualización (m)":286.1,"Estado del cero absoluto":"Provisional","Criterio":"Las cotas relativas proceden del dibujo; la equivalencia absoluta no está confirmada."} | {"boundingBoxM":{"min":[42.578125,50.361753,2.1],"max":[43.028879,50.812507,3.1]},"extentsM":[0.450754,0.450754,1.0],"meshSurfaceM2":1.920001,"meshVolumeM3":0.16,"closedSolid":true,"basis":"Magnitudes de las mallas representadas, no cantidades certificadas de obra, compra o fabricación. Las partes pueden compartir superficies; no se suman como un despiece de materiales."} | {"profileId":"concrete_reinforced","name":"Hormigón armado · gris natural","materialName":"Hormigón armado · clase pendiente de confirmar","physicalMaterialStatus":"Clase no confirmada en la hoja de equipo","physicalMaterialSource":"Geometría de cimentación del fabricante; no se extrapola HA-30 de la nota de pedestales.","appearanceStatus":"criterio_visual","appearanceBasis":"Interpretación visual del material documental; el acabado, tono y parámetros PBR no son una especificación contractual.","note":"La apariencia gráfica no modifica ni confirma la especificación física del material."} | {"elementId":"found_0904_c57c5652bab97f","ifcGuid":"2g6odLUPTV4wT7hKJbpjm5","ifcClass":"IfcFooting","buildingId":"process_plant","buildingName":"Zona de separación de aire","sourceDocumentId":"LHD2609-JG00100-20260904","sourceRepresentationKind":"foundation"} | {"layerId":"foundations","layerName":"Cimentaciones","role":"Cimentación industrial","basis":"Clasificación por función del elemento; no modifica las especificaciones documentales."} | {"profileId":"concrete_reinforced","name":"Hormigón armado · gris natural","status":"criterio_visual","basis":"Interpretación visual del material documental; el acabado, tono y parámetros PBR no son una especificación contractual.","physicalMaterialUnchanged":true} | 0.16 | Hormigón armado · clase pendiente de confirmar | Hormigón armado · gris natural | found_0904_c57c5652bab97f | Geometría de cimentación del fabricante; no se extrapola HA-30 de la nota de pedestales. | Clase no confirmada en la hoja de equipo | concrete_reinforced | [0.666667,0.662745,0.619608] | 0.96 | Zona de separación de aire; BIM · Cimentaciones | 0.450754 | 0.450754 | 1 | 287.1 | 288.1 | F-WT3001 | ["WT3001A","WT3001B","WT3001C","WT3001D"] | [] | 9–9 / 9A–9A | ["25DC/25E1","25DC/25E2","25DC/25E4","25DC/2604","25DC/25E5","2473E"] | F-WT3001/Cimentación común de torres de refrigeración · pilar DZ9 05 | foundation | Geometría de fabricante; implantación absoluta provisional | WT3001A, WT3001B, WT3001C, WT3001D | Cimentaciones de equipos y pedestales del fabricante · revisión recibida 04/09/2026 | 25DC/25E1, 25DC/25E2, 25DC/25E4, 25DC/2604, 25DC/25E5, 2473E | 1 | 2 | 0.16 | Cotas relativas del dibujo. La equivalencia con un datum absoluto está pendiente. | Z del modelo = cota relativa + 1,10 m. Correspondencia provisional con 286,10 m; no es cota de obra confirmada. | Sección y contornos del fabricante; incidencias conservadas | 0.4 | 0.4 | Planta: −2,200 m. Secciones: fondo −2,000 m, losa superior −1,200 m; se adoptan secciones. / La última línea transversal presenta una discrepancia de 4 mm respecto a los ejes de pilares; se conserva la posición de cada contorno fuente.
Cimentación común de torres de refrigeración · pilar DZ9 06 | Parcela industrial Jinhong | Cimentación industrial | Cimentaciones de equipos y pedestales del fabricante · revisión recibida 04/09/2026 | 0.450754 | 0.450754 | 1 | 1.92 | 0.16 | process_plant | Zona de separación de aire | {"name":"Hormigón armado · clase pendiente de confirmar","status":"Clase no confirmada en la hoja de equipo","source":"Geometría de cimentación del fabricante; no se extrapola HA-30 de la nota de pedestales."} | {"documented":[{"label":"Extensión local X","value":0.4,"unit":"m","source":"25DC/25E1, 25DC/25E2, 25DC/25E4, 25DC/2604, 25DC/25E5, 2473E","status":"derivada del contorno CAD"},{"label":"Extensión local Y","value":0.4,"unit":"m","source":"25DC/25E1, 25DC/25E2, 25DC/25E4, 25DC/2604, 25DC/25E5, 2473E","status":"derivada del contorno CAD"},{"label":"Cota inferior relativa adoptada","value":1,"unit":"m","source":"9–9 / 9A–9A","status":"interpretación con conflicto conservado"},{"label":"Cota superior relativa adoptada","value":2,"unit":"m","source":"9–9 / 9A–9A","status":"documentada / separación por material"}],"geometry":[{"label":"Extensión de la malla en X","value":0.4507539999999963,"unit":"m","source":"Geometría releída del IFC; datum absoluto de proceso provisional","status":"derivado"},{"label":"Extensión de la malla en Y","value":0.45075400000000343,"unit":"m","source":"Geometría releída del IFC; datum absoluto de proceso provisional","status":"derivado"},{"label":"Extensión de la malla en Z","value":1.0,"unit":"m","source":"Geometría releída del IFC; datum absoluto de proceso provisional","status":"derivado"},{"label":"Cota inferior de visualización","value":287.1,"unit":"m","source":"Geometría releída del IFC; datum absoluto de proceso provisional","status":"derivado"},{"label":"Cota superior de visualización","value":288.1,"unit":"m","source":"Geometría releída del IFC; datum absoluto de proceso provisional","status":"derivado"}]} | {"documentId":"LHD2609-JG00100-20260904","title":"Cimentaciones de equipos y pedestales del fabricante · revisión recibida 04/09/2026","date":"2026-09-04","sheet":"9–9 / 9A–9A","fileName":"LHD2609-JG00100_20260904.dwg","revisionCaveat":"Fecha de revisión tomada del nombre recibido; cajetines internos mantienen 02/07/2026 y algunos textos de plantilla.","sourceFileSha256":"b42eb027b7bc0b14c38d1d13514f4899b58a732aa8d0ba2ccf10fa2fc3192890"} | provisional | ["Planta: −2,200 m. Secciones: fondo −2,000 m, losa superior −1,200 m; se adoptan secciones.","La última línea transversal presenta una discrepancia de 4 mm respecto a los ejes de pilares; se conserva la posición de cada contorno fuente."] | {"Cota inferior relativa (m)":1,"Cota superior relativa (m)":2,"Cero absoluto de visualización (m)":286.1,"Estado del cero absoluto":"Provisional","Criterio":"Las cotas relativas proceden del dibujo; la equivalencia absoluta no está confirmada."} | {"boundingBoxM":{"min":[36.530793,49.033041,2.1],"max":[36.981547,49.483795,3.1]},"extentsM":[0.450754,0.450754,1.0],"meshSurfaceM2":1.920001,"meshVolumeM3":0.16,"closedSolid":true,"basis":"Magnitudes de las mallas representadas, no cantidades certificadas de obra, compra o fabricación. Las partes pueden compartir superficies; no se suman como un despiece de materiales."} | {"profileId":"concrete_reinforced","name":"Hormigón armado · gris natural","materialName":"Hormigón armado · clase pendiente de confirmar","physicalMaterialStatus":"Clase no confirmada en la hoja de equipo","physicalMaterialSource":"Geometría de cimentación del fabricante; no se extrapola HA-30 de la nota de pedestales.","appearanceStatus":"criterio_visual","appearanceBasis":"Interpretación visual del material documental; el acabado, tono y parámetros PBR no son una especificación contractual.","note":"La apariencia gráfica no modifica ni confirma la especificación física del material."} | {"elementId":"found_0904_39e399198820f7","ifcGuid":"0_NDpZtLfOpv1i2opbzFtE","ifcClass":"IfcFooting","buildingId":"process_plant","buildingName":"Zona de separación de aire","sourceDocumentId":"LHD2609-JG00100-20260904","sourceRepresentationKind":"foundation"} | {"layerId":"foundations","layerName":"Cimentaciones","role":"Cimentación industrial","basis":"Clasificación por función del elemento; no modifica las especificaciones documentales."} | {"profileId":"concrete_reinforced","name":"Hormigón armado · gris natural","status":"criterio_visual","basis":"Interpretación visual del material documental; el acabado, tono y parámetros PBR no son una especificación contractual.","physicalMaterialUnchanged":true} | 0.16 | Hormigón armado · clase pendiente de confirmar | Hormigón armado · gris natural | found_0904_39e399198820f7 | Geometría de cimentación del fabricante; no se extrapola HA-30 de la nota de pedestales. | Clase no confirmada en la hoja de equipo | concrete_reinforced | [0.666667,0.662745,0.619608] | 0.96 | Zona de separación de aire; BIM · Cimentaciones | 0.450754 | 0.450754 | 1 | 287.1 | 288.1 | F-WT3001 | ["WT3001A","WT3001B","WT3001C","WT3001D"] | [] | 9–9 / 9A–9A | ["25DC/25E1","25DC/25E2","25DC/25E4","25DC/2604","25DC/25E5","2473E"] | F-WT3001/Cimentación común de torres de refrigeración · pilar DZ9 06 | foundation | Geometría de fabricante; implantación absoluta provisional | WT3001A, WT3001B, WT3001C, WT3001D | Cimentaciones de equipos y pedestales del fabricante · revisión recibida 04/09/2026 | 25DC/25E1, 25DC/25E2, 25DC/25E4, 25DC/2604, 25DC/25E5, 2473E | 1 | 2 | 0.16 | Cotas relativas del dibujo. La equivalencia con un datum absoluto está pendiente. | Z del modelo = cota relativa + 1,10 m. Correspondencia provisional con 286,10 m; no es cota de obra confirmada. | Sección y contornos del fabricante; incidencias conservadas | 0.4 | 0.4 | Planta: −2,200 m. Secciones: fondo −2,000 m, losa superior −1,200 m; se adoptan secciones. / La última línea transversal presenta una discrepancia de 4 mm respecto a los ejes de pilares; se conserva la posición de cada contorno fuente.
Cimentación común de torres de refrigeración · pilar DZ9 07 | Parcela industrial Jinhong | Cimentación industrial | Cimentaciones de equipos y pedestales del fabricante · revisión recibida 04/09/2026 | 0.450753 | 0.450754 | 1 | 1.92 | 0.16 | process_plant | Zona de separación de aire | {"name":"Hormigón armado · clase pendiente de confirmar","status":"Clase no confirmada en la hoja de equipo","source":"Geometría de cimentación del fabricante; no se extrapola HA-30 de la nota de pedestales."} | {"documented":[{"label":"Extensión local X","value":0.4,"unit":"m","source":"25DC/25E1, 25DC/25E2, 25DC/25E4, 25DC/2604, 25DC/25E5, 2473E","status":"derivada del contorno CAD"},{"label":"Extensión local Y","value":0.4,"unit":"m","source":"25DC/25E1, 25DC/25E2, 25DC/25E4, 25DC/2604, 25DC/25E5, 2473E","status":"derivada del contorno CAD"},{"label":"Cota inferior relativa adoptada","value":1,"unit":"m","source":"9–9 / 9A–9A","status":"interpretación con conflicto conservado"},{"label":"Cota superior relativa adoptada","value":2,"unit":"m","source":"9–9 / 9A–9A","status":"documentada / separación por material"}],"geometry":[{"label":"Extensión de la malla en X","value":0.45075300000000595,"unit":"m","source":"Geometría releída del IFC; datum absoluto de proceso provisional","status":"derivado"},{"label":"Extensión de la malla en Y","value":0.45075400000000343,"unit":"m","source":"Geometría releída del IFC; datum absoluto de proceso provisional","status":"derivado"},{"label":"Extensión de la malla en Z","value":1.0,"unit":"m","source":"Geometría releída del IFC; datum absoluto de proceso provisional","status":"derivado"},{"label":"Cota inferior de visualización","value":287.1,"unit":"m","source":"Geometría releída del IFC; datum absoluto de proceso provisional","status":"derivado"},{"label":"Cota superior de visualización","value":288.1,"unit":"m","source":"Geometría releída del IFC; datum absoluto de proceso provisional","status":"derivado"}]} | {"documentId":"LHD2609-JG00100-20260904","title":"Cimentaciones de equipos y pedestales del fabricante · revisión recibida 04/09/2026","date":"2026-09-04","sheet":"9–9 / 9A–9A","fileName":"LHD2609-JG00100_20260904.dwg","revisionCaveat":"Fecha de revisión tomada del nombre recibido; cajetines internos mantienen 02/07/2026 y algunos textos de plantilla.","sourceFileSha256":"b42eb027b7bc0b14c38d1d13514f4899b58a732aa8d0ba2ccf10fa2fc3192890"} | provisional | ["Planta: −2,200 m. Secciones: fondo −2,000 m, losa superior −1,200 m; se adoptan secciones.","La última línea transversal presenta una discrepancia de 4 mm respecto a los ejes de pilares; se conserva la posición de cada contorno fuente."] | {"Cota inferior relativa (m)":1,"Cota superior relativa (m)":2,"Cero absoluto de visualización (m)":286.1,"Estado del cero absoluto":"Provisional","Criterio":"Las cotas relativas proceden del dibujo; la equivalencia absoluta no está confirmada."} | {"boundingBoxM":{"min":[37.635403,48.881173,2.1],"max":[38.086156,49.331927,3.1]},"extentsM":[0.450753,0.450754,1.0],"meshSurfaceM2":1.919999,"meshVolumeM3":0.16,"closedSolid":true,"basis":"Magnitudes de las mallas representadas, no cantidades certificadas de obra, compra o fabricación. Las partes pueden compartir superficies; no se suman como un despiece de materiales."} | {"profileId":"concrete_reinforced","name":"Hormigón armado · gris natural","materialName":"Hormigón armado · clase pendiente de confirmar","physicalMaterialStatus":"Clase no confirmada en la hoja de equipo","physicalMaterialSource":"Geometría de cimentación del fabricante; no se extrapola HA-30 de la nota de pedestales.","appearanceStatus":"criterio_visual","appearanceBasis":"Interpretación visual del material documental; el acabado, tono y parámetros PBR no son una especificación contractual.","note":"La apariencia gráfica no modifica ni confirma la especificación física del material."} | {"elementId":"found_0904_066c2e41569779","ifcGuid":"2WwReO_xnMGwL5nOyath9C","ifcClass":"IfcFooting","buildingId":"process_plant","buildingName":"Zona de separación de aire","sourceDocumentId":"LHD2609-JG00100-20260904","sourceRepresentationKind":"foundation"} | {"layerId":"foundations","layerName":"Cimentaciones","role":"Cimentación industrial","basis":"Clasificación por función del elemento; no modifica las especificaciones documentales."} | {"profileId":"concrete_reinforced","name":"Hormigón armado · gris natural","status":"criterio_visual","basis":"Interpretación visual del material documental; el acabado, tono y parámetros PBR no son una especificación contractual.","physicalMaterialUnchanged":true} | 0.16 | Hormigón armado · clase pendiente de confirmar | Hormigón armado · gris natural | found_0904_066c2e41569779 | Geometría de cimentación del fabricante; no se extrapola HA-30 de la nota de pedestales. | Clase no confirmada en la hoja de equipo | concrete_reinforced | [0.666667,0.662745,0.619608] | 0.96 | Zona de separación de aire; BIM · Cimentaciones | 0.450753 | 0.450754 | 1 | 287.1 | 288.1 | F-WT3001 | ["WT3001A","WT3001B","WT3001C","WT3001D"] | [] | 9–9 / 9A–9A | ["25DC/25E1","25DC/25E2","25DC/25E4","25DC/2604","25DC/25E5","2473E"] | F-WT3001/Cimentación común de torres de refrigeración · pilar DZ9 07 | foundation | Geometría de fabricante; implantación absoluta provisional | WT3001A, WT3001B, WT3001C, WT3001D | Cimentaciones de equipos y pedestales del fabricante · revisión recibida 04/09/2026 | 25DC/25E1, 25DC/25E2, 25DC/25E4, 25DC/2604, 25DC/25E5, 2473E | 1 | 2 | 0.16 | Cotas relativas del dibujo. La equivalencia con un datum absoluto está pendiente. | Z del modelo = cota relativa + 1,10 m. Correspondencia provisional con 286,10 m; no es cota de obra confirmada. | Sección y contornos del fabricante; incidencias conservadas | 0.4 | 0.4 | Planta: −2,200 m. Secciones: fondo −2,000 m, losa superior −1,200 m; se adoptan secciones. / La última línea transversal presenta una discrepancia de 4 mm respecto a los ejes de pilares; se conserva la posición de cada contorno fuente.
Cimentación común de torres de refrigeración · pilar DZ9 08 | Parcela industrial Jinhong | Cimentación industrial | Cimentaciones de equipos y pedestales del fabricante · revisión recibida 04/09/2026 | 0.450754 | 0.450754 | 1 | 1.92 | 0.16 | process_plant | Zona de separación de aire | {"name":"Hormigón armado · clase pendiente de confirmar","status":"Clase no confirmada en la hoja de equipo","source":"Geometría de cimentación del fabricante; no se extrapola HA-30 de la nota de pedestales."} | {"documented":[{"label":"Extensión local X","value":0.4,"unit":"m","source":"25DC/25E1, 25DC/25E2, 25DC/25E4, 25DC/2604, 25DC/25E5, 2473E","status":"derivada del contorno CAD"},{"label":"Extensión local Y","value":0.4,"unit":"m","source":"25DC/25E1, 25DC/25E2, 25DC/25E4, 25DC/2604, 25DC/25E5, 2473E","status":"derivada del contorno CAD"},{"label":"Cota inferior relativa adoptada","value":1,"unit":"m","source":"9–9 / 9A–9A","status":"interpretación con conflicto conservado"},{"label":"Cota superior relativa adoptada","value":2,"unit":"m","source":"9–9 / 9A–9A","status":"documentada / separación por material"}],"geometry":[{"label":"Extensión de la malla en X","value":0.4507539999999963,"unit":"m","source":"Geometría releída del IFC; datum absoluto de proceso provisional","status":"derivado"},{"label":"Extensión de la malla en Y","value":0.45075400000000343,"unit":"m","source":"Geometría releída del IFC; datum absoluto de proceso provisional","status":"derivado"},{"label":"Extensión de la malla en Z","value":1.0,"unit":"m","source":"Geometría releída del IFC; datum absoluto de proceso provisional","status":"derivado"},{"label":"Cota inferior de visualización","value":287.1,"unit":"m","source":"Geometría releída del IFC; datum absoluto de proceso provisional","status":"derivado"},{"label":"Cota superior de visualización","value":288.1,"unit":"m","source":"Geometría releída del IFC; datum absoluto de proceso provisional","status":"derivado"}]} | {"documentId":"LHD2609-JG00100-20260904","title":"Cimentaciones de equipos y pedestales del fabricante · revisión recibida 04/09/2026","date":"2026-09-04","sheet":"9–9 / 9A–9A","fileName":"LHD2609-JG00100_20260904.dwg","revisionCaveat":"Fecha de revisión tomada del nombre recibido; cajetines internos mantienen 02/07/2026 y algunos textos de plantilla.","sourceFileSha256":"b42eb027b7bc0b14c38d1d13514f4899b58a732aa8d0ba2ccf10fa2fc3192890"} | provisional | ["Planta: −2,200 m. Secciones: fondo −2,000 m, losa superior −1,200 m; se adoptan secciones.","La última línea transversal presenta una discrepancia de 4 mm respecto a los ejes de pilares; se conserva la posición de cada contorno fuente."] | {"Cota inferior relativa (m)":1,"Cota superior relativa (m)":2,"Cero absoluto de visualización (m)":286.1,"Estado del cero absoluto":"Provisional","Criterio":"Las cotas relativas proceden del dibujo; la equivalencia absoluta no está confirmada."} | {"boundingBoxM":{"min":[38.449742,48.769214,2.1],"max":[38.900496,49.219968,3.1]},"extentsM":[0.450754,0.450754,1.0],"meshSurfaceM2":1.920001,"meshVolumeM3":0.16,"closedSolid":true,"basis":"Magnitudes de las mallas representadas, no cantidades certificadas de obra, compra o fabricación. Las partes pueden compartir superficies; no se suman como un despiece de materiales."} | {"profileId":"concrete_reinforced","name":"Hormigón armado · gris natural","materialName":"Hormigón armado · clase pendiente de confirmar","physicalMaterialStatus":"Clase no confirmada en la hoja de equipo","physicalMaterialSource":"Geometría de cimentación del fabricante; no se extrapola HA-30 de la nota de pedestales.","appearanceStatus":"criterio_visual","appearanceBasis":"Interpretación visual del material documental; el acabado, tono y parámetros PBR no son una especificación contractual.","note":"La apariencia gráfica no modifica ni confirma la especificación física del material."} | {"elementId":"found_0904_fe68a533f9e20c","ifcGuid":"2_A__fZnHTUhKTSe7MIqeS","ifcClass":"IfcFooting","buildingId":"process_plant","buildingName":"Zona de separación de aire","sourceDocumentId":"LHD2609-JG00100-20260904","sourceRepresentationKind":"foundation"} | {"layerId":"foundations","layerName":"Cimentaciones","role":"Cimentación industrial","basis":"Clasificación por función del elemento; no modifica las especificaciones documentales."} | {"profileId":"concrete_reinforced","name":"Hormigón armado · gris natural","status":"criterio_visual","basis":"Interpretación visual del material documental; el acabado, tono y parámetros PBR no son una especificación contractual.","physicalMaterialUnchanged":true} | 0.16 | Hormigón armado · clase pendiente de confirmar | Hormigón armado · gris natural | found_0904_fe68a533f9e20c | Geometría de cimentación del fabricante; no se extrapola HA-30 de la nota de pedestales. | Clase no confirmada en la hoja de equipo | concrete_reinforced | [0.666667,0.662745,0.619608] | 0.96 | Zona de separación de aire; BIM · Cimentaciones | 0.450754 | 0.450754 | 1 | 287.1 | 288.1 | F-WT3001 | ["WT3001A","WT3001B","WT3001C","WT3001D"] | [] | 9–9 / 9A–9A | ["25DC/25E1","25DC/25E2","25DC/25E4","25DC/2604","25DC/25E5","2473E"] | F-WT3001/Cimentación común de torres de refrigeración · pilar DZ9 08 | foundation | Geometría de fabricante; implantación absoluta provisional | WT3001A, WT3001B, WT3001C, WT3001D | Cimentaciones de equipos y pedestales del fabricante · revisión recibida 04/09/2026 | 25DC/25E1, 25DC/25E2, 25DC/25E4, 25DC/2604, 25DC/25E5, 2473E | 1 | 2 | 0.16 | Cotas relativas del dibujo. La equivalencia con un datum absoluto está pendiente. | Z del modelo = cota relativa + 1,10 m. Correspondencia provisional con 286,10 m; no es cota de obra confirmada. | Sección y contornos del fabricante; incidencias conservadas | 0.4 | 0.4 | Planta: −2,200 m. Secciones: fondo −2,000 m, losa superior −1,200 m; se adoptan secciones. / La última línea transversal presenta una discrepancia de 4 mm respecto a los ejes de pilares; se conserva la posición de cada contorno fuente.
Cimentación común de torres de refrigeración · pilar DZ9 09 | Parcela industrial Jinhong | Cimentación industrial | Cimentaciones de equipos y pedestales del fabricante · revisión recibida 04/09/2026 | 0.450754 | 0.450754 | 1 | 1.92 | 0.16 | process_plant | Zona de separación de aire | {"name":"Hormigón armado · clase pendiente de confirmar","status":"Clase no confirmada en la hoja de equipo","source":"Geometría de cimentación del fabricante; no se extrapola HA-30 de la nota de pedestales."} | {"documented":[{"label":"Extensión local X","value":0.4,"unit":"m","source":"25DC/25E1, 25DC/25E2, 25DC/25E4, 25DC/2604, 25DC/25E5, 2473E","status":"derivada del contorno CAD"},{"label":"Extensión local Y","value":0.4,"unit":"m","source":"25DC/25E1, 25DC/25E2, 25DC/25E4, 25DC/2604, 25DC/25E5, 2473E","status":"derivada del contorno CAD"},{"label":"Cota inferior relativa adoptada","value":1,"unit":"m","source":"9–9 / 9A–9A","status":"interpretación con conflicto conservado"},{"label":"Cota superior relativa adoptada","value":2,"unit":"m","source":"9–9 / 9A–9A","status":"documentada / separación por material"}],"geometry":[{"label":"Extensión de la malla en X","value":0.45075400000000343,"unit":"m","source":"Geometría releída del IFC; datum absoluto de proceso provisional","status":"derivado"},{"label":"Extensión de la malla en Y","value":0.45075400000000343,"unit":"m","source":"Geometría releída del IFC; datum absoluto de proceso provisional","status":"derivado"},{"label":"Extensión de la malla en Z","value":1.0,"unit":"m","source":"Geometría releída del IFC; datum absoluto de proceso provisional","status":"derivado"},{"label":"Cota inferior de visualización","value":287.1,"unit":"m","source":"Geometría releída del IFC; datum absoluto de proceso provisional","status":"derivado"},{"label":"Cota superior de visualización","value":288.1,"unit":"m","source":"Geometría releída del IFC; datum absoluto de proceso provisional","status":"derivado"}]} | {"documentId":"LHD2609-JG00100-20260904","title":"Cimentaciones de equipos y pedestales del fabricante · revisión recibida 04/09/2026","date":"2026-09-04","sheet":"9–9 / 9A–9A","fileName":"LHD2609-JG00100_20260904.dwg","revisionCaveat":"Fecha de revisión tomada del nombre recibido; cajetines internos mantienen 02/07/2026 y algunos textos de plantilla.","sourceFileSha256":"b42eb027b7bc0b14c38d1d13514f4899b58a732aa8d0ba2ccf10fa2fc3192890"} | provisional | ["Planta: −2,200 m. Secciones: fondo −2,000 m, losa superior −1,200 m; se adoptan secciones.","La última línea transversal presenta una discrepancia de 4 mm respecto a los ejes de pilares; se conserva la posición de cada contorno fuente."] | {"Cota inferior relativa (m)":1,"Cota superior relativa (m)":2,"Cero absoluto de visualización (m)":286.1,"Estado del cero absoluto":"Provisional","Criterio":"Las cotas relativas proceden del dibujo; la equivalencia absoluta no está confirmada."} | {"boundingBoxM":{"min":[40.3677,48.505523,2.1],"max":[40.818454,48.956277,3.1]},"extentsM":[0.450754,0.450754,1.0],"meshSurfaceM2":1.920001,"meshVolumeM3":0.16,"closedSolid":true,"basis":"Magnitudes de las mallas representadas, no cantidades certificadas de obra, compra o fabricación. Las partes pueden compartir superficies; no se suman como un despiece de materiales."} | {"profileId":"concrete_reinforced","name":"Hormigón armado · gris natural","materialName":"Hormigón armado · clase pendiente de confirmar","physicalMaterialStatus":"Clase no confirmada en la hoja de equipo","physicalMaterialSource":"Geometría de cimentación del fabricante; no se extrapola HA-30 de la nota de pedestales.","appearanceStatus":"criterio_visual","appearanceBasis":"Interpretación visual del material documental; el acabado, tono y parámetros PBR no son una especificación contractual.","note":"La apariencia gráfica no modifica ni confirma la especificación física del material."} | {"elementId":"found_0904_b4fc99a4de059c","ifcGuid":"2miiPzg8rHIvFt0DThJQBq","ifcClass":"IfcFooting","buildingId":"process_plant","buildingName":"Zona de separación de aire","sourceDocumentId":"LHD2609-JG00100-20260904","sourceRepresentationKind":"foundation"} | {"layerId":"foundations","layerName":"Cimentaciones","role":"Cimentación industrial","basis":"Clasificación por función del elemento; no modifica las especificaciones documentales."} | {"profileId":"concrete_reinforced","name":"Hormigón armado · gris natural","status":"criterio_visual","basis":"Interpretación visual del material documental; el acabado, tono y parámetros PBR no son una especificación contractual.","physicalMaterialUnchanged":true} | 0.16 | Hormigón armado · clase pendiente de confirmar | Hormigón armado · gris natural | found_0904_b4fc99a4de059c | Geometría de cimentación del fabricante; no se extrapola HA-30 de la nota de pedestales. | Clase no confirmada en la hoja de equipo | concrete_reinforced | [0.666667,0.662745,0.619608] | 0.96 | Zona de separación de aire; BIM · Cimentaciones | 0.450754 | 0.450754 | 1 | 287.1 | 288.1 | F-WT3001 | ["WT3001A","WT3001B","WT3001C","WT3001D"] | [] | 9–9 / 9A–9A | ["25DC/25E1","25DC/25E2","25DC/25E4","25DC/2604","25DC/25E5","2473E"] | F-WT3001/Cimentación común de torres de refrigeración · pilar DZ9 09 | foundation | Geometría de fabricante; implantación absoluta provisional | WT3001A, WT3001B, WT3001C, WT3001D | Cimentaciones de equipos y pedestales del fabricante · revisión recibida 04/09/2026 | 25DC/25E1, 25DC/25E2, 25DC/25E4, 25DC/2604, 25DC/25E5, 2473E | 1 | 2 | 0.16 | Cotas relativas del dibujo. La equivalencia con un datum absoluto está pendiente. | Z del modelo = cota relativa + 1,10 m. Correspondencia provisional con 286,10 m; no es cota de obra confirmada. | Sección y contornos del fabricante; incidencias conservadas | 0.4 | 0.4 | Planta: −2,200 m. Secciones: fondo −2,000 m, losa superior −1,200 m; se adoptan secciones. / La última línea transversal presenta una discrepancia de 4 mm respecto a los ejes de pilares; se conserva la posición de cada contorno fuente.
Cimentación común de torres de refrigeración · pilar DZ9 10 | Parcela industrial Jinhong | Cimentación industrial | Cimentaciones de equipos y pedestales del fabricante · revisión recibida 04/09/2026 | 0.450754 | 0.450754 | 1 | 1.92 | 0.16 | process_plant | Zona de separación de aire | {"name":"Hormigón armado · clase pendiente de confirmar","status":"Clase no confirmada en la hoja de equipo","source":"Geometría de cimentación del fabricante; no se extrapola HA-30 de la nota de pedestales."} | {"documented":[{"label":"Extensión local X","value":0.4,"unit":"m","source":"25DC/25E1, 25DC/25E2, 25DC/25E4, 25DC/2604, 25DC/25E5, 2473E","status":"derivada del contorno CAD"},{"label":"Extensión local Y","value":0.4,"unit":"m","source":"25DC/25E1, 25DC/25E2, 25DC/25E4, 25DC/2604, 25DC/25E5, 2473E","status":"derivada del contorno CAD"},{"label":"Cota inferior relativa adoptada","value":1,"unit":"m","source":"9–9 / 9A–9A","status":"interpretación con conflicto conservado"},{"label":"Cota superior relativa adoptada","value":2,"unit":"m","source":"9–9 / 9A–9A","status":"documentada / separación por material"}],"geometry":[{"label":"Extensión de la malla en X","value":0.45075400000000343,"unit":"m","source":"Geometría releída del IFC; datum absoluto de proceso provisional","status":"derivado"},{"label":"Extensión de la malla en Y","value":0.45075400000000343,"unit":"m","source":"Geometría releída del IFC; datum absoluto de proceso provisional","status":"derivado"},{"label":"Extensión de la malla en Z","value":1.0,"unit":"m","source":"Geometría releída del IFC; datum absoluto de proceso provisional","status":"derivado"},{"label":"Cota inferior de visualización","value":287.1,"unit":"m","source":"Geometría releída del IFC; datum absoluto de proceso provisional","status":"derivado"},{"label":"Cota superior de visualización","value":288.1,"unit":"m","source":"Geometría releída del IFC; datum absoluto de proceso provisional","status":"derivado"}]} | {"documentId":"LHD2609-JG00100-20260904","title":"Cimentaciones de equipos y pedestales del fabricante · revisión recibida 04/09/2026","date":"2026-09-04","sheet":"9–9 / 9A–9A","fileName":"LHD2609-JG00100_20260904.dwg","revisionCaveat":"Fecha de revisión tomada del nombre recibido; cajetines internos mantienen 02/07/2026 y algunos textos de plantilla.","sourceFileSha256":"b42eb027b7bc0b14c38d1d13514f4899b58a732aa8d0ba2ccf10fa2fc3192890"} | provisional | ["Planta: −2,200 m. Secciones: fondo −2,000 m, losa superior −1,200 m; se adoptan secciones.","La última línea transversal presenta una discrepancia de 4 mm respecto a los ejes de pilares; se conserva la posición de cada contorno fuente."] | {"Cota inferior relativa (m)":1,"Cota superior relativa (m)":2,"Cero absoluto de visualización (m)":286.1,"Estado del cero absoluto":"Provisional","Criterio":"Las cotas relativas proceden del dibujo; la equivalencia absoluta no está confirmada."} | {"boundingBoxM":{"min":[42.286649,48.241696,2.1],"max":[42.737403,48.69245,3.1]},"extentsM":[0.450754,0.450754,1.0],"meshSurfaceM2":1.92,"meshVolumeM3":0.16,"closedSolid":true,"basis":"Magnitudes de las mallas representadas, no cantidades certificadas de obra, compra o fabricación. Las partes pueden compartir superficies; no se suman como un despiece de materiales."} | {"profileId":"concrete_reinforced","name":"Hormigón armado · gris natural","materialName":"Hormigón armado · clase pendiente de confirmar","physicalMaterialStatus":"Clase no confirmada en la hoja de equipo","physicalMaterialSource":"Geometría de cimentación del fabricante; no se extrapola HA-30 de la nota de pedestales.","appearanceStatus":"criterio_visual","appearanceBasis":"Interpretación visual del material documental; el acabado, tono y parámetros PBR no son una especificación contractual.","note":"La apariencia gráfica no modifica ni confirma la especificación física del material."} | {"elementId":"found_0904_41db176a04fb20","ifcGuid":"14LihGWBXRsQAOp9XwnLTU","ifcClass":"IfcFooting","buildingId":"process_plant","buildingName":"Zona de separación de aire","sourceDocumentId":"LHD2609-JG00100-20260904","sourceRepresentationKind":"foundation"} | {"layerId":"foundations","layerName":"Cimentaciones","role":"Cimentación industrial","basis":"Clasificación por función del elemento; no modifica las especificaciones documentales."} | {"profileId":"concrete_reinforced","name":"Hormigón armado · gris natural","status":"criterio_visual","basis":"Interpretación visual del material documental; el acabado, tono y parámetros PBR no son una especificación contractual.","physicalMaterialUnchanged":true} | 0.16 | Hormigón armado · clase pendiente de confirmar | Hormigón armado · gris natural | found_0904_41db176a04fb20 | Geometría de cimentación del fabricante; no se extrapola HA-30 de la nota de pedestales. | Clase no confirmada en la hoja de equipo | concrete_reinforced | [0.666667,0.662745,0.619608] | 0.96 | Zona de separación de aire; BIM · Cimentaciones | 0.450754 | 0.450754 | 1 | 287.1 | 288.1 | F-WT3001 | ["WT3001A","WT3001B","WT3001C","WT3001D"] | [] | 9–9 / 9A–9A | ["25DC/25E1","25DC/25E2","25DC/25E4","25DC/2604","25DC/25E5","2473E"] | F-WT3001/Cimentación común de torres de refrigeración · pilar DZ9 10 | foundation | Geometría de fabricante; implantación absoluta provisional | WT3001A, WT3001B, WT3001C, WT3001D | Cimentaciones de equipos y pedestales del fabricante · revisión recibida 04/09/2026 | 25DC/25E1, 25DC/25E2, 25DC/25E4, 25DC/2604, 25DC/25E5, 2473E | 1 | 2 | 0.16 | Cotas relativas del dibujo. La equivalencia con un datum absoluto está pendiente. | Z del modelo = cota relativa + 1,10 m. Correspondencia provisional con 286,10 m; no es cota de obra confirmada. | Sección y contornos del fabricante; incidencias conservadas | 0.4 | 0.4 | Planta: −2,200 m. Secciones: fondo −2,000 m, losa superior −1,200 m; se adoptan secciones. / La última línea transversal presenta una discrepancia de 4 mm respecto a los ejes de pilares; se conserva la posición de cada contorno fuente.
Cimentación común de torres de refrigeración · pilar DZ9 11 | Parcela industrial Jinhong | Cimentación industrial | Cimentaciones de equipos y pedestales del fabricante · revisión recibida 04/09/2026 | 0.450754 | 0.450754 | 1 | 1.92 | 0.16 | process_plant | Zona de separación de aire | {"name":"Hormigón armado · clase pendiente de confirmar","status":"Clase no confirmada en la hoja de equipo","source":"Geometría de cimentación del fabricante; no se extrapola HA-30 de la nota de pedestales."} | {"documented":[{"label":"Extensión local X","value":0.4,"unit":"m","source":"25DC/25E1, 25DC/25E2, 25DC/25E4, 25DC/2604, 25DC/25E5, 2473E","status":"derivada del contorno CAD"},{"label":"Extensión local Y","value":0.4,"unit":"m","source":"25DC/25E1, 25DC/25E2, 25DC/25E4, 25DC/2604, 25DC/25E5, 2473E","status":"derivada del contorno CAD"},{"label":"Cota inferior relativa adoptada","value":1,"unit":"m","source":"9–9 / 9A–9A","status":"interpretación con conflicto conservado"},{"label":"Cota superior relativa adoptada","value":2,"unit":"m","source":"9–9 / 9A–9A","status":"documentada / separación por material"}],"geometry":[{"label":"Extensión de la malla en X","value":0.45075400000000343,"unit":"m","source":"Geometría releída del IFC; datum absoluto de proceso provisional","status":"derivado"},{"label":"Extensión de la malla en Y","value":0.4507539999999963,"unit":"m","source":"Geometría releída del IFC; datum absoluto de proceso provisional","status":"derivado"},{"label":"Extensión de la malla en Z","value":1.0,"unit":"m","source":"Geometría releída del IFC; datum absoluto de proceso provisional","status":"derivado"},{"label":"Cota inferior de visualización","value":287.1,"unit":"m","source":"Geometría releída del IFC; datum absoluto de proceso provisional","status":"derivado"},{"label":"Cota superior de visualización","value":288.1,"unit":"m","source":"Geometría releída del IFC; datum absoluto de proceso provisional","status":"derivado"}]} | {"documentId":"LHD2609-JG00100-20260904","title":"Cimentaciones de equipos y pedestales del fabricante · revisión recibida 04/09/2026","date":"2026-09-04","sheet":"9–9 / 9A–9A","fileName":"LHD2609-JG00100_20260904.dwg","revisionCaveat":"Fecha de revisión tomada del nombre recibido; cajetines internos mantienen 02/07/2026 y algunos textos de plantilla.","sourceFileSha256":"b42eb027b7bc0b14c38d1d13514f4899b58a732aa8d0ba2ccf10fa2fc3192890"} | provisional | ["Planta: −2,200 m. Secciones: fondo −2,000 m, losa superior −1,200 m; se adoptan secciones.","La última línea transversal presenta una discrepancia de 4 mm respecto a los ejes de pilares; se conserva la posición de cada contorno fuente."] | {"Cota inferior relativa (m)":1,"Cota superior relativa (m)":2,"Cero absoluto de visualización (m)":286.1,"Estado del cero absoluto":"Provisional","Criterio":"Las cotas relativas proceden del dibujo; la equivalencia absoluta no está confirmada."} | {"boundingBoxM":{"min":[36.239317,46.912984,2.1],"max":[36.690071,47.363738,3.1]},"extentsM":[0.450754,0.450754,1.0],"meshSurfaceM2":1.92,"meshVolumeM3":0.16,"closedSolid":true,"basis":"Magnitudes de las mallas representadas, no cantidades certificadas de obra, compra o fabricación. Las partes pueden compartir superficies; no se suman como un despiece de materiales."} | {"profileId":"concrete_reinforced","name":"Hormigón armado · gris natural","materialName":"Hormigón armado · clase pendiente de confirmar","physicalMaterialStatus":"Clase no confirmada en la hoja de equipo","physicalMaterialSource":"Geometría de cimentación del fabricante; no se extrapola HA-30 de la nota de pedestales.","appearanceStatus":"criterio_visual","appearanceBasis":"Interpretación visual del material documental; el acabado, tono y parámetros PBR no son una especificación contractual.","note":"La apariencia gráfica no modifica ni confirma la especificación física del material."} | {"elementId":"found_0904_226854faa7ca3d","ifcGuid":"3lyc9LjjLRnxcG3uJF1hy$","ifcClass":"IfcFooting","buildingId":"process_plant","buildingName":"Zona de separación de aire","sourceDocumentId":"LHD2609-JG00100-20260904","sourceRepresentationKind":"foundation"} | {"layerId":"foundations","layerName":"Cimentaciones","role":"Cimentación industrial","basis":"Clasificación por función del elemento; no modifica las especificaciones documentales."} | {"profileId":"concrete_reinforced","name":"Hormigón armado · gris natural","status":"criterio_visual","basis":"Interpretación visual del material documental; el acabado, tono y parámetros PBR no son una especificación contractual.","physicalMaterialUnchanged":true} | 0.16 | Hormigón armado · clase pendiente de confirmar | Hormigón armado · gris natural | found_0904_226854faa7ca3d | Geometría de cimentación del fabricante; no se extrapola HA-30 de la nota de pedestales. | Clase no confirmada en la hoja de equipo | concrete_reinforced | [0.666667,0.662745,0.619608] | 0.96 | Zona de separación de aire; BIM · Cimentaciones | 0.450754 | 0.450754 | 1 | 287.1 | 288.1 | F-WT3001 | ["WT3001A","WT3001B","WT3001C","WT3001D"] | [] | 9–9 / 9A–9A | ["25DC/25E1","25DC/25E2","25DC/25E4","25DC/2604","25DC/25E5","2473E"] | F-WT3001/Cimentación común de torres de refrigeración · pilar DZ9 11 | foundation | Geometría de fabricante; implantación absoluta provisional | WT3001A, WT3001B, WT3001C, WT3001D | Cimentaciones de equipos y pedestales del fabricante · revisión recibida 04/09/2026 | 25DC/25E1, 25DC/25E2, 25DC/25E4, 25DC/2604, 25DC/25E5, 2473E | 1 | 2 | 0.16 | Cotas relativas del dibujo. La equivalencia con un datum absoluto está pendiente. | Z del modelo = cota relativa + 1,10 m. Correspondencia provisional con 286,10 m; no es cota de obra confirmada. | Sección y contornos del fabricante; incidencias conservadas | 0.4 | 0.4 | Planta: −2,200 m. Secciones: fondo −2,000 m, losa superior −1,200 m; se adoptan secciones. / La última línea transversal presenta una discrepancia de 4 mm respecto a los ejes de pilares; se conserva la posición de cada contorno fuente.
Cimentación común de torres de refrigeración · pilar DZ9 12 | Parcela industrial Jinhong | Cimentación industrial | Cimentaciones de equipos y pedestales del fabricante · revisión recibida 04/09/2026 | 0.450754 | 0.450754 | 1 | 1.92 | 0.16 | process_plant | Zona de separación de aire | {"name":"Hormigón armado · clase pendiente de confirmar","status":"Clase no confirmada en la hoja de equipo","source":"Geometría de cimentación del fabricante; no se extrapola HA-30 de la nota de pedestales."} | {"documented":[{"label":"Extensión local X","value":0.4,"unit":"m","source":"25DC/25E1, 25DC/25E2, 25DC/25E4, 25DC/2604, 25DC/25E5, 2473E","status":"derivada del contorno CAD"},{"label":"Extensión local Y","value":0.4,"unit":"m","source":"25DC/25E1, 25DC/25E2, 25DC/25E4, 25DC/2604, 25DC/25E5, 2473E","status":"derivada del contorno CAD"},{"label":"Cota inferior relativa adoptada","value":1,"unit":"m","source":"9–9 / 9A–9A","status":"interpretación con conflicto conservado"},{"label":"Cota superior relativa adoptada","value":2,"unit":"m","source":"9–9 / 9A–9A","status":"documentada / separación por material"}],"geometry":[{"label":"Extensión de la malla en X","value":0.4507539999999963,"unit":"m","source":"Geometría releída del IFC; datum absoluto de proceso provisional","status":"derivado"},{"label":"Extensión de la malla en Y","value":0.4507539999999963,"unit":"m","source":"Geometría releída del IFC; datum absoluto de proceso provisional","status":"derivado"},{"label":"Extensión de la malla en Z","value":1.0,"unit":"m","source":"Geometría releída del IFC; datum absoluto de proceso provisional","status":"derivado"},{"label":"Cota inferior de visualización","value":287.1,"unit":"m","source":"Geometría releída del IFC; datum absoluto de proceso provisional","status":"derivado"},{"label":"Cota superior de visualización","value":288.1,"unit":"m","source":"Geometría releída del IFC; datum absoluto de proceso provisional","status":"derivado"}]} | {"documentId":"LHD2609-JG00100-20260904","title":"Cimentaciones de equipos y pedestales del fabricante · revisión recibida 04/09/2026","date":"2026-09-04","sheet":"9–9 / 9A–9A","fileName":"LHD2609-JG00100_20260904.dwg","revisionCaveat":"Fecha de revisión tomada del nombre recibido; cajetines internos mantienen 02/07/2026 y algunos textos de plantilla.","sourceFileSha256":"b42eb027b7bc0b14c38d1d13514f4899b58a732aa8d0ba2ccf10fa2fc3192890"} | provisional | ["Planta: −2,200 m. Secciones: fondo −2,000 m, losa superior −1,200 m; se adoptan secciones.","La última línea transversal presenta una discrepancia de 4 mm respecto a los ejes de pilares; se conserva la posición de cada contorno fuente."] | {"Cota inferior relativa (m)":1,"Cota superior relativa (m)":2,"Cero absoluto de visualización (m)":286.1,"Estado del cero absoluto":"Provisional","Criterio":"Las cotas relativas proceden del dibujo; la equivalencia absoluta no está confirmada."} | {"boundingBoxM":{"min":[37.343926,46.761116,2.1],"max":[37.79468,47.21187,3.1]},"extentsM":[0.450754,0.450754,1.0],"meshSurfaceM2":1.92,"meshVolumeM3":0.16,"closedSolid":true,"basis":"Magnitudes de las mallas representadas, no cantidades certificadas de obra, compra o fabricación. Las partes pueden compartir superficies; no se suman como un despiece de materiales."} | {"profileId":"concrete_reinforced","name":"Hormigón armado · gris natural","materialName":"Hormigón armado · clase pendiente de confirmar","physicalMaterialStatus":"Clase no confirmada en la hoja de equipo","physicalMaterialSource":"Geometría de cimentación del fabricante; no se extrapola HA-30 de la nota de pedestales.","appearanceStatus":"criterio_visual","appearanceBasis":"Interpretación visual del material documental; el acabado, tono y parámetros PBR no son una especificación contractual.","note":"La apariencia gráfica no modifica ni confirma la especificación física del material."} | {"elementId":"found_0904_064cdcb9794539","ifcGuid":"3E00CdW6rIzw_DaBKBuCZw","ifcClass":"IfcFooting","buildingId":"process_plant","buildingName":"Zona de separación de aire","sourceDocumentId":"LHD2609-JG00100-20260904","sourceRepresentationKind":"foundation"} | {"layerId":"foundations","layerName":"Cimentaciones","role":"Cimentación industrial","basis":"Clasificación por función del elemento; no modifica las especificaciones documentales."} | {"profileId":"concrete_reinforced","name":"Hormigón armado · gris natural","status":"criterio_visual","basis":"Interpretación visual del material documental; el acabado, tono y parámetros PBR no son una especificación contractual.","physicalMaterialUnchanged":true} | 0.16 | Hormigón armado · clase pendiente de confirmar | Hormigón armado · gris natural | found_0904_064cdcb9794539 | Geometría de cimentación del fabricante; no se extrapola HA-30 de la nota de pedestales. | Clase no confirmada en la hoja de equipo | concrete_reinforced | [0.666667,0.662745,0.619608] | 0.96 | Zona de separación de aire; BIM · Cimentaciones | 0.450754 | 0.450754 | 1 | 287.1 | 288.1 | F-WT3001 | ["WT3001A","WT3001B","WT3001C","WT3001D"] | [] | 9–9 / 9A–9A | ["25DC/25E1","25DC/25E2","25DC/25E4","25DC/2604","25DC/25E5","2473E"] | F-WT3001/Cimentación común de torres de refrigeración · pilar DZ9 12 | foundation | Geometría de fabricante; implantación absoluta provisional | WT3001A, WT3001B, WT3001C, WT3001D | Cimentaciones de equipos y pedestales del fabricante · revisión recibida 04/09/2026 | 25DC/25E1, 25DC/25E2, 25DC/25E4, 25DC/2604, 25DC/25E5, 2473E | 1 | 2 | 0.16 | Cotas relativas del dibujo. La equivalencia con un datum absoluto está pendiente. | Z del modelo = cota relativa + 1,10 m. Correspondencia provisional con 286,10 m; no es cota de obra confirmada. | Sección y contornos del fabricante; incidencias conservadas | 0.4 | 0.4 | Planta: −2,200 m. Secciones: fondo −2,000 m, losa superior −1,200 m; se adoptan secciones. / La última línea transversal presenta una discrepancia de 4 mm respecto a los ejes de pilares; se conserva la posición de cada contorno fuente.
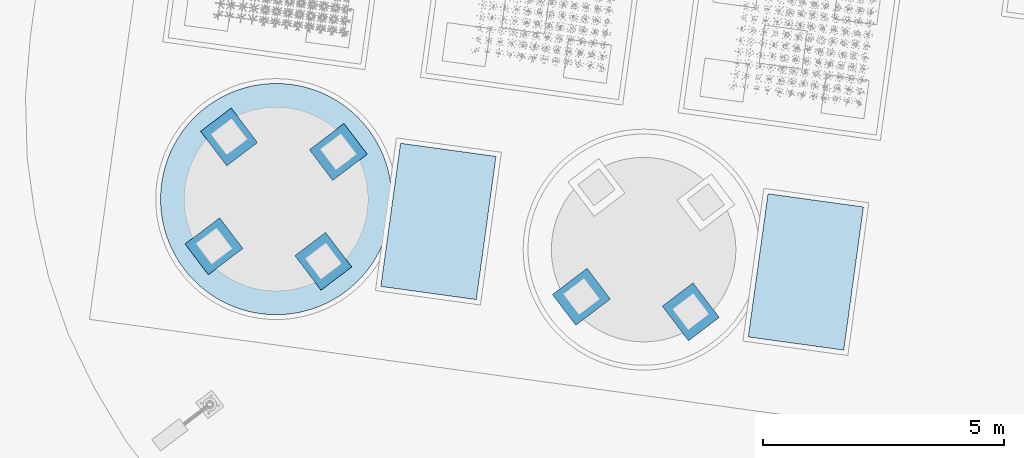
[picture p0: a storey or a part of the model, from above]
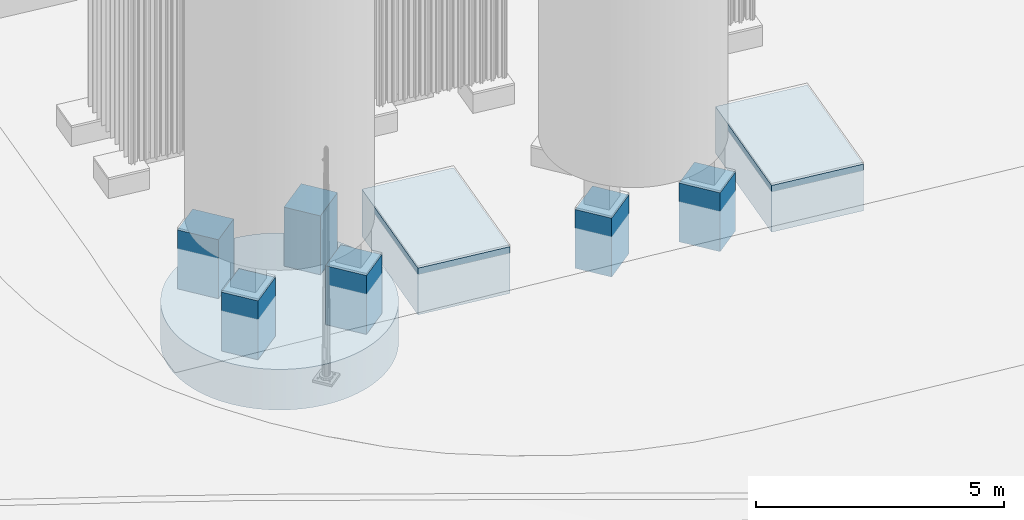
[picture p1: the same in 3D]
Properties of the parts of a building model (IFC4), part 72 of 134

# IfcFooting (214)
Name | In | Description = category = Categoria = Funcion | Document | ExtensionX (m) | ExtensionY (m) | ExtensionZ (m) | SuperficieDeLaMalla (m2) | VolumenGeometrico (m3) | buildingId | buildingName | material | dimensions | JH_InformacionBIM, source = DocumentoFuente | JH_InformacionBIM, status = EstadoDeInformacion | issues = IncidenciasPendientes | positioning = PosicionYEstado | geometryMetrics | materialAppearance | visualizationIdentity | classification | appearance | Volumen geométrico (m³) | JH_Trazabilidad, Material = name | Acabado de visualización = Acabado | Identificador | JH_EvidenciaDeMaterial, source | JH_EvidenciaDeMaterial, status | Perfil | ColorRGB | Rugosidad | Group | Extensión de la malla en X (m) | Extensión de la malla en Y (m) | Extensión de la malla en Z (m) = Espesor o altura real de sección (m) | Cota inferior de visualización (m) | Cota superior de visualización (m) | assemblyId = Conjunto de cimentación | equipmentIds | supportPositionIds | sectionRef = Sección de referencia | sourceCadHandles | stableElementKey | representationKind | geometryStatus | Equipos asociados | Documento de origen | Identificadores CAD de referencia | Cota inferior relativa (m) = Cota inferior relativa adoptada (m) | Cota superior relativa (m) = Cota superior relativa adoptada (m) | Área de planta (m²) | Referencia vertical | Implantación para visualización | Estado de la geometría | Extensión local X (m) | Extensión local Y (m) | Incidencias de origen
Cimentación común de torres de refrigeración · pilar DZ9 13 | Parcela industrial Jinhong | Cimentación industrial | Cimentaciones de equipos y pedestales del fabricante · revisión recibida 04/09/2026 | 0.450754 | 0.450754 | 1 | 1.92 | 0.16 | process_plant | Zona de separación de aire | {"name":"Hormigón armado · clase pendiente de confirmar","status":"Clase no confirmada en la hoja de equipo","source":"Geometría de cimentación del fabricante; no se extrapola HA-30 de la nota de pedestales."} | {"documented":[{"label":"Extensión local X","value":0.4,"unit":"m","source":"25DC/25E1, 25DC/25E2, 25DC/25E4, 25DC/2604, 25DC/25E5, 2473E","status":"derivada del contorno CAD"},{"label":"Extensión local Y","value":0.4,"unit":"m","source":"25DC/25E1, 25DC/25E2, 25DC/25E4, 25DC/2604, 25DC/25E5, 2473E","status":"derivada del contorno CAD"},{"label":"Cota inferior relativa adoptada","value":1,"unit":"m","source":"9–9 / 9A–9A","status":"interpretación con conflicto conservado"},{"label":"Cota superior relativa adoptada","value":2,"unit":"m","source":"9–9 / 9A–9A","status":"documentada / separación por material"}],"geometry":[{"label":"Extensión de la malla en X","value":0.45075400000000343,"unit":"m","source":"Geometría releída del IFC; datum absoluto de proceso provisional","status":"derivado"},{"label":"Extensión de la malla en Y","value":0.4507539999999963,"unit":"m","source":"Geometría releída del IFC; datum absoluto de proceso provisional","status":"derivado"},{"label":"Extensión de la malla en Z","value":1.0,"unit":"m","source":"Geometría releída del IFC; datum absoluto de proceso provisional","status":"derivado"},{"label":"Cota inferior de visualización","value":287.1,"unit":"m","source":"Geometría releída del IFC; datum absoluto de proceso provisional","status":"derivado"},{"label":"Cota superior de visualización","value":288.1,"unit":"m","source":"Geometría releída del IFC; datum absoluto de proceso provisional","status":"derivado"}]} | {"documentId":"LHD2609-JG00100-20260904","title":"Cimentaciones de equipos y pedestales del fabricante · revisión recibida 04/09/2026","date":"2026-09-04","sheet":"9–9 / 9A–9A","fileName":"LHD2609-JG00100_20260904.dwg","revisionCaveat":"Fecha de revisión tomada del nombre recibido; cajetines internos mantienen 02/07/2026 y algunos textos de plantilla.","sourceFileSha256":"b42eb027b7bc0b14c38d1d13514f4899b58a732aa8d0ba2ccf10fa2fc3192890"} | provisional | ["Planta: −2,200 m. Secciones: fondo −2,000 m, losa superior −1,200 m; se adoptan secciones.","La última línea transversal presenta una discrepancia de 4 mm respecto a los ejes de pilares; se conserva la posición de cada contorno fuente."] | {"Cota inferior relativa (m)":1,"Cota superior relativa (m)":2,"Cero absoluto de visualización (m)":286.1,"Estado del cero absoluto":"Provisional","Criterio":"Las cotas relativas proceden del dibujo; la equivalencia absoluta no está confirmada."} | {"boundingBoxM":{"min":[38.158266,46.649157,2.1],"max":[38.60902,47.099911,3.1]},"extentsM":[0.450754,0.450754,1.0],"meshSurfaceM2":1.920001,"meshVolumeM3":0.16,"closedSolid":true,"basis":"Magnitudes de las mallas representadas, no cantidades certificadas de obra, compra o fabricación. Las partes pueden compartir superficies; no se suman como un despiece de materiales."} | {"profileId":"concrete_reinforced","name":"Hormigón armado · gris natural","materialName":"Hormigón armado · clase pendiente de confirmar","physicalMaterialStatus":"Clase no confirmada en la hoja de equipo","physicalMaterialSource":"Geometría de cimentación del fabricante; no se extrapola HA-30 de la nota de pedestales.","appearanceStatus":"criterio_visual","appearanceBasis":"Interpretación visual del material documental; el acabado, tono y parámetros PBR no son una especificación contractual.","note":"La apariencia gráfica no modifica ni confirma la especificación física del material."} | {"elementId":"found_0904_1d1f902ca0997b","ifcGuid":"1IZpE$h_LR4fKDfX0znpYG","ifcClass":"IfcFooting","buildingId":"process_plant","buildingName":"Zona de separación de aire","sourceDocumentId":"LHD2609-JG00100-20260904","sourceRepresentationKind":"foundation"} | {"layerId":"foundations","layerName":"Cimentaciones","role":"Cimentación industrial","basis":"Clasificación por función del elemento; no modifica las especificaciones documentales."} | {"profileId":"concrete_reinforced","name":"Hormigón armado · gris natural","status":"criterio_visual","basis":"Interpretación visual del material documental; el acabado, tono y parámetros PBR no son una especificación contractual.","physicalMaterialUnchanged":true} | 0.16 | Hormigón armado · clase pendiente de confirmar | Hormigón armado · gris natural | found_0904_1d1f902ca0997b | Geometría de cimentación del fabricante; no se extrapola HA-30 de la nota de pedestales. | Clase no confirmada en la hoja de equipo | concrete_reinforced | [0.666667,0.662745,0.619608] | 0.96 | Zona de separación de aire; BIM · Cimentaciones | 0.450754 | 0.450754 | 1 | 287.1 | 288.1 | F-WT3001 | ["WT3001A","WT3001B","WT3001C","WT3001D"] | [] | 9–9 / 9A–9A | ["25DC/25E1","25DC/25E2","25DC/25E4","25DC/2604","25DC/25E5","2473E"] | F-WT3001/Cimentación común de torres de refrigeración · pilar DZ9 13 | foundation | Geometría de fabricante; implantación absoluta provisional | WT3001A, WT3001B, WT3001C, WT3001D | Cimentaciones de equipos y pedestales del fabricante · revisión recibida 04/09/2026 | 25DC/25E1, 25DC/25E2, 25DC/25E4, 25DC/2604, 25DC/25E5, 2473E | 1 | 2 | 0.16 | Cotas relativas del dibujo. La equivalencia con un datum absoluto está pendiente. | Z del modelo = cota relativa + 1,10 m. Correspondencia provisional con 286,10 m; no es cota de obra confirmada. | Sección y contornos del fabricante; incidencias conservadas | 0.4 | 0.4 | Planta: −2,200 m. Secciones: fondo −2,000 m, losa superior −1,200 m; se adoptan secciones. / La última línea transversal presenta una discrepancia de 4 mm respecto a los ejes de pilares; se conserva la posición de cada contorno fuente.
Cimentación común de torres de refrigeración · pilar DZ9 14 | Parcela industrial Jinhong | Cimentación industrial | Cimentaciones de equipos y pedestales del fabricante · revisión recibida 04/09/2026 | 0.450754 | 0.450754 | 1 | 1.92 | 0.16 | process_plant | Zona de separación de aire | {"name":"Hormigón armado · clase pendiente de confirmar","status":"Clase no confirmada en la hoja de equipo","source":"Geometría de cimentación del fabricante; no se extrapola HA-30 de la nota de pedestales."} | {"documented":[{"label":"Extensión local X","value":0.4,"unit":"m","source":"25DC/25E1, 25DC/25E2, 25DC/25E4, 25DC/2604, 25DC/25E5, 2473E","status":"derivada del contorno CAD"},{"label":"Extensión local Y","value":0.4,"unit":"m","source":"25DC/25E1, 25DC/25E2, 25DC/25E4, 25DC/2604, 25DC/25E5, 2473E","status":"derivada del contorno CAD"},{"label":"Cota inferior relativa adoptada","value":1,"unit":"m","source":"9–9 / 9A–9A","status":"interpretación con conflicto conservado"},{"label":"Cota superior relativa adoptada","value":2,"unit":"m","source":"9–9 / 9A–9A","status":"documentada / separación por material"}],"geometry":[{"label":"Extensión de la malla en X","value":0.4507539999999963,"unit":"m","source":"Geometría releída del IFC; datum absoluto de proceso provisional","status":"derivado"},{"label":"Extensión de la malla en Y","value":0.4507539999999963,"unit":"m","source":"Geometría releída del IFC; datum absoluto de proceso provisional","status":"derivado"},{"label":"Extensión de la malla en Z","value":1.0,"unit":"m","source":"Geometría releída del IFC; datum absoluto de proceso provisional","status":"derivado"},{"label":"Cota inferior de visualización","value":287.1,"unit":"m","source":"Geometría releída del IFC; datum absoluto de proceso provisional","status":"derivado"},{"label":"Cota superior de visualización","value":288.1,"unit":"m","source":"Geometría releída del IFC; datum absoluto de proceso provisional","status":"derivado"}]} | {"documentId":"LHD2609-JG00100-20260904","title":"Cimentaciones de equipos y pedestales del fabricante · revisión recibida 04/09/2026","date":"2026-09-04","sheet":"9–9 / 9A–9A","fileName":"LHD2609-JG00100_20260904.dwg","revisionCaveat":"Fecha de revisión tomada del nombre recibido; cajetines internos mantienen 02/07/2026 y algunos textos de plantilla.","sourceFileSha256":"b42eb027b7bc0b14c38d1d13514f4899b58a732aa8d0ba2ccf10fa2fc3192890"} | provisional | ["Planta: −2,200 m. Secciones: fondo −2,000 m, losa superior −1,200 m; se adoptan secciones.","La última línea transversal presenta una discrepancia de 4 mm respecto a los ejes de pilares; se conserva la posición de cada contorno fuente."] | {"Cota inferior relativa (m)":1,"Cota superior relativa (m)":2,"Cero absoluto de visualización (m)":286.1,"Estado del cero absoluto":"Provisional","Criterio":"Las cotas relativas proceden del dibujo; la equivalencia absoluta no está confirmada."} | {"boundingBoxM":{"min":[40.076224,46.385466,2.1],"max":[40.526978,46.83622,3.1]},"extentsM":[0.450754,0.450754,1.0],"meshSurfaceM2":1.920001,"meshVolumeM3":0.16,"closedSolid":true,"basis":"Magnitudes de las mallas representadas, no cantidades certificadas de obra, compra o fabricación. Las partes pueden compartir superficies; no se suman como un despiece de materiales."} | {"profileId":"concrete_reinforced","name":"Hormigón armado · gris natural","materialName":"Hormigón armado · clase pendiente de confirmar","physicalMaterialStatus":"Clase no confirmada en la hoja de equipo","physicalMaterialSource":"Geometría de cimentación del fabricante; no se extrapola HA-30 de la nota de pedestales.","appearanceStatus":"criterio_visual","appearanceBasis":"Interpretación visual del material documental; el acabado, tono y parámetros PBR no son una especificación contractual.","note":"La apariencia gráfica no modifica ni confirma la especificación física del material."} | {"elementId":"found_0904_9c0f73461f655a","ifcGuid":"1Ihul04MfLcQDhu5tU6h5a","ifcClass":"IfcFooting","buildingId":"process_plant","buildingName":"Zona de separación de aire","sourceDocumentId":"LHD2609-JG00100-20260904","sourceRepresentationKind":"foundation"} | {"layerId":"foundations","layerName":"Cimentaciones","role":"Cimentación industrial","basis":"Clasificación por función del elemento; no modifica las especificaciones documentales."} | {"profileId":"concrete_reinforced","name":"Hormigón armado · gris natural","status":"criterio_visual","basis":"Interpretación visual del material documental; el acabado, tono y parámetros PBR no son una especificación contractual.","physicalMaterialUnchanged":true} | 0.16 | Hormigón armado · clase pendiente de confirmar | Hormigón armado · gris natural | found_0904_9c0f73461f655a | Geometría de cimentación del fabricante; no se extrapola HA-30 de la nota de pedestales. | Clase no confirmada en la hoja de equipo | concrete_reinforced | [0.666667,0.662745,0.619608] | 0.96 | Zona de separación de aire; BIM · Cimentaciones | 0.450754 | 0.450754 | 1 | 287.1 | 288.1 | F-WT3001 | ["WT3001A","WT3001B","WT3001C","WT3001D"] | [] | 9–9 / 9A–9A | ["25DC/25E1","25DC/25E2","25DC/25E4","25DC/2604","25DC/25E5","2473E"] | F-WT3001/Cimentación común de torres de refrigeración · pilar DZ9 14 | foundation | Geometría de fabricante; implantación absoluta provisional | WT3001A, WT3001B, WT3001C, WT3001D | Cimentaciones de equipos y pedestales del fabricante · revisión recibida 04/09/2026 | 25DC/25E1, 25DC/25E2, 25DC/25E4, 25DC/2604, 25DC/25E5, 2473E | 1 | 2 | 0.16 | Cotas relativas del dibujo. La equivalencia con un datum absoluto está pendiente. | Z del modelo = cota relativa + 1,10 m. Correspondencia provisional con 286,10 m; no es cota de obra confirmada. | Sección y contornos del fabricante; incidencias conservadas | 0.4 | 0.4 | Planta: −2,200 m. Secciones: fondo −2,000 m, losa superior −1,200 m; se adoptan secciones. / La última línea transversal presenta una discrepancia de 4 mm respecto a los ejes de pilares; se conserva la posición de cada contorno fuente.
Cimentación común de torres de refrigeración · pilar DZ9 15 | Parcela industrial Jinhong | Cimentación industrial | Cimentaciones de equipos y pedestales del fabricante · revisión recibida 04/09/2026 | 0.450753 | 0.450754 | 1 | 1.92 | 0.16 | process_plant | Zona de separación de aire | {"name":"Hormigón armado · clase pendiente de confirmar","status":"Clase no confirmada en la hoja de equipo","source":"Geometría de cimentación del fabricante; no se extrapola HA-30 de la nota de pedestales."} | {"documented":[{"label":"Extensión local X","value":0.4,"unit":"m","source":"25DC/25E1, 25DC/25E2, 25DC/25E4, 25DC/2604, 25DC/25E5, 2473E","status":"derivada del contorno CAD"},{"label":"Extensión local Y","value":0.4,"unit":"m","source":"25DC/25E1, 25DC/25E2, 25DC/25E4, 25DC/2604, 25DC/25E5, 2473E","status":"derivada del contorno CAD"},{"label":"Cota inferior relativa adoptada","value":1,"unit":"m","source":"9–9 / 9A–9A","status":"interpretación con conflicto conservado"},{"label":"Cota superior relativa adoptada","value":2,"unit":"m","source":"9–9 / 9A–9A","status":"documentada / separación por material"}],"geometry":[{"label":"Extensión de la malla en X","value":0.45075299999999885,"unit":"m","source":"Geometría releída del IFC; datum absoluto de proceso provisional","status":"derivado"},{"label":"Extensión de la malla en Y","value":0.4507539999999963,"unit":"m","source":"Geometría releída del IFC; datum absoluto de proceso provisional","status":"derivado"},{"label":"Extensión de la malla en Z","value":1.0,"unit":"m","source":"Geometría releída del IFC; datum absoluto de proceso provisional","status":"derivado"},{"label":"Cota inferior de visualización","value":287.1,"unit":"m","source":"Geometría releída del IFC; datum absoluto de proceso provisional","status":"derivado"},{"label":"Cota superior de visualización","value":288.1,"unit":"m","source":"Geometría releída del IFC; datum absoluto de proceso provisional","status":"derivado"}]} | {"documentId":"LHD2609-JG00100-20260904","title":"Cimentaciones de equipos y pedestales del fabricante · revisión recibida 04/09/2026","date":"2026-09-04","sheet":"9–9 / 9A–9A","fileName":"LHD2609-JG00100_20260904.dwg","revisionCaveat":"Fecha de revisión tomada del nombre recibido; cajetines internos mantienen 02/07/2026 y algunos textos de plantilla.","sourceFileSha256":"b42eb027b7bc0b14c38d1d13514f4899b58a732aa8d0ba2ccf10fa2fc3192890"} | provisional | ["Planta: −2,200 m. Secciones: fondo −2,000 m, losa superior −1,200 m; se adoptan secciones.","La última línea transversal presenta una discrepancia de 4 mm respecto a los ejes de pilares; se conserva la posición de cada contorno fuente."] | {"Cota inferior relativa (m)":1,"Cota superior relativa (m)":2,"Cero absoluto de visualización (m)":286.1,"Estado del cero absoluto":"Provisional","Criterio":"Las cotas relativas proceden del dibujo; la equivalencia absoluta no está confirmada."} | {"boundingBoxM":{"min":[41.995173,46.121639,2.1],"max":[42.445926,46.572393,3.1]},"extentsM":[0.450753,0.450754,1.0],"meshSurfaceM2":1.919999,"meshVolumeM3":0.16,"closedSolid":true,"basis":"Magnitudes de las mallas representadas, no cantidades certificadas de obra, compra o fabricación. Las partes pueden compartir superficies; no se suman como un despiece de materiales."} | {"profileId":"concrete_reinforced","name":"Hormigón armado · gris natural","materialName":"Hormigón armado · clase pendiente de confirmar","physicalMaterialStatus":"Clase no confirmada en la hoja de equipo","physicalMaterialSource":"Geometría de cimentación del fabricante; no se extrapola HA-30 de la nota de pedestales.","appearanceStatus":"criterio_visual","appearanceBasis":"Interpretación visual del material documental; el acabado, tono y parámetros PBR no son una especificación contractual.","note":"La apariencia gráfica no modifica ni confirma la especificación física del material."} | {"elementId":"found_0904_7ec2add80b8399","ifcGuid":"1OgT2hXknIt8e$09Kn_Ecx","ifcClass":"IfcFooting","buildingId":"process_plant","buildingName":"Zona de separación de aire","sourceDocumentId":"LHD2609-JG00100-20260904","sourceRepresentationKind":"foundation"} | {"layerId":"foundations","layerName":"Cimentaciones","role":"Cimentación industrial","basis":"Clasificación por función del elemento; no modifica las especificaciones documentales."} | {"profileId":"concrete_reinforced","name":"Hormigón armado · gris natural","status":"criterio_visual","basis":"Interpretación visual del material documental; el acabado, tono y parámetros PBR no son una especificación contractual.","physicalMaterialUnchanged":true} | 0.16 | Hormigón armado · clase pendiente de confirmar | Hormigón armado · gris natural | found_0904_7ec2add80b8399 | Geometría de cimentación del fabricante; no se extrapola HA-30 de la nota de pedestales. | Clase no confirmada en la hoja de equipo | concrete_reinforced | [0.666667,0.662745,0.619608] | 0.96 | Zona de separación de aire; BIM · Cimentaciones | 0.450753 | 0.450754 | 1 | 287.1 | 288.1 | F-WT3001 | ["WT3001A","WT3001B","WT3001C","WT3001D"] | [] | 9–9 / 9A–9A | ["25DC/25E1","25DC/25E2","25DC/25E4","25DC/2604","25DC/25E5","2473E"] | F-WT3001/Cimentación común de torres de refrigeración · pilar DZ9 15 | foundation | Geometría de fabricante; implantación absoluta provisional | WT3001A, WT3001B, WT3001C, WT3001D | Cimentaciones de equipos y pedestales del fabricante · revisión recibida 04/09/2026 | 25DC/25E1, 25DC/25E2, 25DC/25E4, 25DC/2604, 25DC/25E5, 2473E | 1 | 2 | 0.16 | Cotas relativas del dibujo. La equivalencia con un datum absoluto está pendiente. | Z del modelo = cota relativa + 1,10 m. Correspondencia provisional con 286,10 m; no es cota de obra confirmada. | Sección y contornos del fabricante; incidencias conservadas | 0.4 | 0.4 | Planta: −2,200 m. Secciones: fondo −2,000 m, losa superior −1,200 m; se adoptan secciones. / La última línea transversal presenta una discrepancia de 4 mm respecto a los ejes de pilares; se conserva la posición de cada contorno fuente.
Cimentación común de torres de refrigeración · pilar DZ9 16 | Parcela industrial Jinhong | Cimentación industrial | Cimentaciones de equipos y pedestales del fabricante · revisión recibida 04/09/2026 | 0.450754 | 0.450754 | 1 | 1.92 | 0.16 | process_plant | Zona de separación de aire | {"name":"Hormigón armado · clase pendiente de confirmar","status":"Clase no confirmada en la hoja de equipo","source":"Geometría de cimentación del fabricante; no se extrapola HA-30 de la nota de pedestales."} | {"documented":[{"label":"Extensión local X","value":0.4,"unit":"m","source":"25DC/25E1, 25DC/25E2, 25DC/25E4, 25DC/2604, 25DC/25E5, 2473E","status":"derivada del contorno CAD"},{"label":"Extensión local Y","value":0.4,"unit":"m","source":"25DC/25E1, 25DC/25E2, 25DC/25E4, 25DC/2604, 25DC/25E5, 2473E","status":"derivada del contorno CAD"},{"label":"Cota inferior relativa adoptada","value":1,"unit":"m","source":"9–9 / 9A–9A","status":"interpretación con conflicto conservado"},{"label":"Cota superior relativa adoptada","value":2,"unit":"m","source":"9–9 / 9A–9A","status":"documentada / separación por material"}],"geometry":[{"label":"Extensión de la malla en X","value":0.45075400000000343,"unit":"m","source":"Geometría releída del IFC; datum absoluto de proceso provisional","status":"derivado"},{"label":"Extensión de la malla en Y","value":0.45075400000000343,"unit":"m","source":"Geometría releída del IFC; datum absoluto de proceso provisional","status":"derivado"},{"label":"Extensión de la malla en Z","value":1.0,"unit":"m","source":"Geometría releída del IFC; datum absoluto de proceso provisional","status":"derivado"},{"label":"Cota inferior de visualización","value":287.1,"unit":"m","source":"Geometría releída del IFC; datum absoluto de proceso provisional","status":"derivado"},{"label":"Cota superior de visualización","value":288.1,"unit":"m","source":"Geometría releída del IFC; datum absoluto de proceso provisional","status":"derivado"}]} | {"documentId":"LHD2609-JG00100-20260904","title":"Cimentaciones de equipos y pedestales del fabricante · revisión recibida 04/09/2026","date":"2026-09-04","sheet":"9–9 / 9A–9A","fileName":"LHD2609-JG00100_20260904.dwg","revisionCaveat":"Fecha de revisión tomada del nombre recibido; cajetines internos mantienen 02/07/2026 y algunos textos de plantilla.","sourceFileSha256":"b42eb027b7bc0b14c38d1d13514f4899b58a732aa8d0ba2ccf10fa2fc3192890"} | provisional | ["Planta: −2,200 m. Secciones: fondo −2,000 m, losa superior −1,200 m; se adoptan secciones.","La última línea transversal presenta una discrepancia de 4 mm respecto a los ejes de pilares; se conserva la posición de cada contorno fuente."] | {"Cota inferior relativa (m)":1,"Cota superior relativa (m)":2,"Cero absoluto de visualización (m)":286.1,"Estado del cero absoluto":"Provisional","Criterio":"Las cotas relativas proceden del dibujo; la equivalencia absoluta no está confirmada."} | {"boundingBoxM":{"min":[35.947841,44.792927,2.1],"max":[36.398595,45.243681,3.1]},"extentsM":[0.450754,0.450754,1.0],"meshSurfaceM2":1.920001,"meshVolumeM3":0.16,"closedSolid":true,"basis":"Magnitudes de las mallas representadas, no cantidades certificadas de obra, compra o fabricación. Las partes pueden compartir superficies; no se suman como un despiece de materiales."} | {"profileId":"concrete_reinforced","name":"Hormigón armado · gris natural","materialName":"Hormigón armado · clase pendiente de confirmar","physicalMaterialStatus":"Clase no confirmada en la hoja de equipo","physicalMaterialSource":"Geometría de cimentación del fabricante; no se extrapola HA-30 de la nota de pedestales.","appearanceStatus":"criterio_visual","appearanceBasis":"Interpretación visual del material documental; el acabado, tono y parámetros PBR no son una especificación contractual.","note":"La apariencia gráfica no modifica ni confirma la especificación física del material."} | {"elementId":"found_0904_564a0ade694ea8","ifcGuid":"3tEIi1t$zNcRWoBADCE28d","ifcClass":"IfcFooting","buildingId":"process_plant","buildingName":"Zona de separación de aire","sourceDocumentId":"LHD2609-JG00100-20260904","sourceRepresentationKind":"foundation"} | {"layerId":"foundations","layerName":"Cimentaciones","role":"Cimentación industrial","basis":"Clasificación por función del elemento; no modifica las especificaciones documentales."} | {"profileId":"concrete_reinforced","name":"Hormigón armado · gris natural","status":"criterio_visual","basis":"Interpretación visual del material documental; el acabado, tono y parámetros PBR no son una especificación contractual.","physicalMaterialUnchanged":true} | 0.16 | Hormigón armado · clase pendiente de confirmar | Hormigón armado · gris natural | found_0904_564a0ade694ea8 | Geometría de cimentación del fabricante; no se extrapola HA-30 de la nota de pedestales. | Clase no confirmada en la hoja de equipo | concrete_reinforced | [0.666667,0.662745,0.619608] | 0.96 | Zona de separación de aire; BIM · Cimentaciones | 0.450754 | 0.450754 | 1 | 287.1 | 288.1 | F-WT3001 | ["WT3001A","WT3001B","WT3001C","WT3001D"] | [] | 9–9 / 9A–9A | ["25DC/25E1","25DC/25E2","25DC/25E4","25DC/2604","25DC/25E5","2473E"] | F-WT3001/Cimentación común de torres de refrigeración · pilar DZ9 16 | foundation | Geometría de fabricante; implantación absoluta provisional | WT3001A, WT3001B, WT3001C, WT3001D | Cimentaciones de equipos y pedestales del fabricante · revisión recibida 04/09/2026 | 25DC/25E1, 25DC/25E2, 25DC/25E4, 25DC/2604, 25DC/25E5, 2473E | 1 | 2 | 0.16 | Cotas relativas del dibujo. La equivalencia con un datum absoluto está pendiente. | Z del modelo = cota relativa + 1,10 m. Correspondencia provisional con 286,10 m; no es cota de obra confirmada. | Sección y contornos del fabricante; incidencias conservadas | 0.4 | 0.4 | Planta: −2,200 m. Secciones: fondo −2,000 m, losa superior −1,200 m; se adoptan secciones. / La última línea transversal presenta una discrepancia de 4 mm respecto a los ejes de pilares; se conserva la posición de cada contorno fuente.
Cimentación común de torres de refrigeración · pilar DZ9 17 | Parcela industrial Jinhong | Cimentación industrial | Cimentaciones de equipos y pedestales del fabricante · revisión recibida 04/09/2026 | 0.450754 | 0.450754 | 1 | 1.92 | 0.16 | process_plant | Zona de separación de aire | {"name":"Hormigón armado · clase pendiente de confirmar","status":"Clase no confirmada en la hoja de equipo","source":"Geometría de cimentación del fabricante; no se extrapola HA-30 de la nota de pedestales."} | {"documented":[{"label":"Extensión local X","value":0.4,"unit":"m","source":"25DC/25E1, 25DC/25E2, 25DC/25E4, 25DC/2604, 25DC/25E5, 2473E","status":"derivada del contorno CAD"},{"label":"Extensión local Y","value":0.4,"unit":"m","source":"25DC/25E1, 25DC/25E2, 25DC/25E4, 25DC/2604, 25DC/25E5, 2473E","status":"derivada del contorno CAD"},{"label":"Cota inferior relativa adoptada","value":1,"unit":"m","source":"9–9 / 9A–9A","status":"interpretación con conflicto conservado"},{"label":"Cota superior relativa adoptada","value":2,"unit":"m","source":"9–9 / 9A–9A","status":"documentada / separación por material"}],"geometry":[{"label":"Extensión de la malla en X","value":0.4507539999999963,"unit":"m","source":"Geometría releída del IFC; datum absoluto de proceso provisional","status":"derivado"},{"label":"Extensión de la malla en Y","value":0.45075400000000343,"unit":"m","source":"Geometría releída del IFC; datum absoluto de proceso provisional","status":"derivado"},{"label":"Extensión de la malla en Z","value":1.0,"unit":"m","source":"Geometría releída del IFC; datum absoluto de proceso provisional","status":"derivado"},{"label":"Cota inferior de visualización","value":287.1,"unit":"m","source":"Geometría releída del IFC; datum absoluto de proceso provisional","status":"derivado"},{"label":"Cota superior de visualización","value":288.1,"unit":"m","source":"Geometría releída del IFC; datum absoluto de proceso provisional","status":"derivado"}]} | {"documentId":"LHD2609-JG00100-20260904","title":"Cimentaciones de equipos y pedestales del fabricante · revisión recibida 04/09/2026","date":"2026-09-04","sheet":"9–9 / 9A–9A","fileName":"LHD2609-JG00100_20260904.dwg","revisionCaveat":"Fecha de revisión tomada del nombre recibido; cajetines internos mantienen 02/07/2026 y algunos textos de plantilla.","sourceFileSha256":"b42eb027b7bc0b14c38d1d13514f4899b58a732aa8d0ba2ccf10fa2fc3192890"} | provisional | ["Planta: −2,200 m. Secciones: fondo −2,000 m, losa superior −1,200 m; se adoptan secciones.","La última línea transversal presenta una discrepancia de 4 mm respecto a los ejes de pilares; se conserva la posición de cada contorno fuente."] | {"Cota inferior relativa (m)":1,"Cota superior relativa (m)":2,"Cero absoluto de visualización (m)":286.1,"Estado del cero absoluto":"Provisional","Criterio":"Las cotas relativas proceden del dibujo; la equivalencia absoluta no está confirmada."} | {"boundingBoxM":{"min":[37.05245,44.641059,2.1],"max":[37.503204,45.091813,3.1]},"extentsM":[0.450754,0.450754,1.0],"meshSurfaceM2":1.920001,"meshVolumeM3":0.16,"closedSolid":true,"basis":"Magnitudes de las mallas representadas, no cantidades certificadas de obra, compra o fabricación. Las partes pueden compartir superficies; no se suman como un despiece de materiales."} | {"profileId":"concrete_reinforced","name":"Hormigón armado · gris natural","materialName":"Hormigón armado · clase pendiente de confirmar","physicalMaterialStatus":"Clase no confirmada en la hoja de equipo","physicalMaterialSource":"Geometría de cimentación del fabricante; no se extrapola HA-30 de la nota de pedestales.","appearanceStatus":"criterio_visual","appearanceBasis":"Interpretación visual del material documental; el acabado, tono y parámetros PBR no son una especificación contractual.","note":"La apariencia gráfica no modifica ni confirma la especificación física del material."} | {"elementId":"found_0904_fb64bea7845d30","ifcGuid":"06DJ3hu05T0g$A9m8gkENv","ifcClass":"IfcFooting","buildingId":"process_plant","buildingName":"Zona de separación de aire","sourceDocumentId":"LHD2609-JG00100-20260904","sourceRepresentationKind":"foundation"} | {"layerId":"foundations","layerName":"Cimentaciones","role":"Cimentación industrial","basis":"Clasificación por función del elemento; no modifica las especificaciones documentales."} | {"profileId":"concrete_reinforced","name":"Hormigón armado · gris natural","status":"criterio_visual","basis":"Interpretación visual del material documental; el acabado, tono y parámetros PBR no son una especificación contractual.","physicalMaterialUnchanged":true} | 0.16 | Hormigón armado · clase pendiente de confirmar | Hormigón armado · gris natural | found_0904_fb64bea7845d30 | Geometría de cimentación del fabricante; no se extrapola HA-30 de la nota de pedestales. | Clase no confirmada en la hoja de equipo | concrete_reinforced | [0.666667,0.662745,0.619608] | 0.96 | Zona de separación de aire; BIM · Cimentaciones | 0.450754 | 0.450754 | 1 | 287.1 | 288.1 | F-WT3001 | ["WT3001A","WT3001B","WT3001C","WT3001D"] | [] | 9–9 / 9A–9A | ["25DC/25E1","25DC/25E2","25DC/25E4","25DC/2604","25DC/25E5","2473E"] | F-WT3001/Cimentación común de torres de refrigeración · pilar DZ9 17 | foundation | Geometría de fabricante; implantación absoluta provisional | WT3001A, WT3001B, WT3001C, WT3001D | Cimentaciones de equipos y pedestales del fabricante · revisión recibida 04/09/2026 | 25DC/25E1, 25DC/25E2, 25DC/25E4, 25DC/2604, 25DC/25E5, 2473E | 1 | 2 | 0.16 | Cotas relativas del dibujo. La equivalencia con un datum absoluto está pendiente. | Z del modelo = cota relativa + 1,10 m. Correspondencia provisional con 286,10 m; no es cota de obra confirmada. | Sección y contornos del fabricante; incidencias conservadas | 0.4 | 0.4 | Planta: −2,200 m. Secciones: fondo −2,000 m, losa superior −1,200 m; se adoptan secciones. / La última línea transversal presenta una discrepancia de 4 mm respecto a los ejes de pilares; se conserva la posición de cada contorno fuente.
Cimentación común de torres de refrigeración · pilar DZ9 18 | Parcela industrial Jinhong | Cimentación industrial | Cimentaciones de equipos y pedestales del fabricante · revisión recibida 04/09/2026 | 0.450754 | 0.450754 | 1 | 1.92 | 0.16 | process_plant | Zona de separación de aire | {"name":"Hormigón armado · clase pendiente de confirmar","status":"Clase no confirmada en la hoja de equipo","source":"Geometría de cimentación del fabricante; no se extrapola HA-30 de la nota de pedestales."} | {"documented":[{"label":"Extensión local X","value":0.4,"unit":"m","source":"25DC/25E1, 25DC/25E2, 25DC/25E4, 25DC/2604, 25DC/25E5, 2473E","status":"derivada del contorno CAD"},{"label":"Extensión local Y","value":0.4,"unit":"m","source":"25DC/25E1, 25DC/25E2, 25DC/25E4, 25DC/2604, 25DC/25E5, 2473E","status":"derivada del contorno CAD"},{"label":"Cota inferior relativa adoptada","value":1,"unit":"m","source":"9–9 / 9A–9A","status":"interpretación con conflicto conservado"},{"label":"Cota superior relativa adoptada","value":2,"unit":"m","source":"9–9 / 9A–9A","status":"documentada / separación por material"}],"geometry":[{"label":"Extensión de la malla en X","value":0.45075400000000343,"unit":"m","source":"Geometría releída del IFC; datum absoluto de proceso provisional","status":"derivado"},{"label":"Extensión de la malla en Y","value":0.45075400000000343,"unit":"m","source":"Geometría releída del IFC; datum absoluto de proceso provisional","status":"derivado"},{"label":"Extensión de la malla en Z","value":1.0,"unit":"m","source":"Geometría releída del IFC; datum absoluto de proceso provisional","status":"derivado"},{"label":"Cota inferior de visualización","value":287.1,"unit":"m","source":"Geometría releída del IFC; datum absoluto de proceso provisional","status":"derivado"},{"label":"Cota superior de visualización","value":288.1,"unit":"m","source":"Geometría releída del IFC; datum absoluto de proceso provisional","status":"derivado"}]} | {"documentId":"LHD2609-JG00100-20260904","title":"Cimentaciones de equipos y pedestales del fabricante · revisión recibida 04/09/2026","date":"2026-09-04","sheet":"9–9 / 9A–9A","fileName":"LHD2609-JG00100_20260904.dwg","revisionCaveat":"Fecha de revisión tomada del nombre recibido; cajetines internos mantienen 02/07/2026 y algunos textos de plantilla.","sourceFileSha256":"b42eb027b7bc0b14c38d1d13514f4899b58a732aa8d0ba2ccf10fa2fc3192890"} | provisional | ["Planta: −2,200 m. Secciones: fondo −2,000 m, losa superior −1,200 m; se adoptan secciones.","La última línea transversal presenta una discrepancia de 4 mm respecto a los ejes de pilares; se conserva la posición de cada contorno fuente."] | {"Cota inferior relativa (m)":1,"Cota superior relativa (m)":2,"Cero absoluto de visualización (m)":286.1,"Estado del cero absoluto":"Provisional","Criterio":"Las cotas relativas proceden del dibujo; la equivalencia absoluta no está confirmada."} | {"boundingBoxM":{"min":[37.866789,44.5291,2.1],"max":[38.317543,44.979854,3.1]},"extentsM":[0.450754,0.450754,1.0],"meshSurfaceM2":1.920001,"meshVolumeM3":0.16,"closedSolid":true,"basis":"Magnitudes de las mallas representadas, no cantidades certificadas de obra, compra o fabricación. Las partes pueden compartir superficies; no se suman como un despiece de materiales."} | {"profileId":"concrete_reinforced","name":"Hormigón armado · gris natural","materialName":"Hormigón armado · clase pendiente de confirmar","physicalMaterialStatus":"Clase no confirmada en la hoja de equipo","physicalMaterialSource":"Geometría de cimentación del fabricante; no se extrapola HA-30 de la nota de pedestales.","appearanceStatus":"criterio_visual","appearanceBasis":"Interpretación visual del material documental; el acabado, tono y parámetros PBR no son una especificación contractual.","note":"La apariencia gráfica no modifica ni confirma la especificación física del material."} | {"elementId":"found_0904_9c5b6c2fd318d0","ifcGuid":"2gDL1sphHJRPVlvPWxuaUX","ifcClass":"IfcFooting","buildingId":"process_plant","buildingName":"Zona de separación de aire","sourceDocumentId":"LHD2609-JG00100-20260904","sourceRepresentationKind":"foundation"} | {"layerId":"foundations","layerName":"Cimentaciones","role":"Cimentación industrial","basis":"Clasificación por función del elemento; no modifica las especificaciones documentales."} | {"profileId":"concrete_reinforced","name":"Hormigón armado · gris natural","status":"criterio_visual","basis":"Interpretación visual del material documental; el acabado, tono y parámetros PBR no son una especificación contractual.","physicalMaterialUnchanged":true} | 0.16 | Hormigón armado · clase pendiente de confirmar | Hormigón armado · gris natural | found_0904_9c5b6c2fd318d0 | Geometría de cimentación del fabricante; no se extrapola HA-30 de la nota de pedestales. | Clase no confirmada en la hoja de equipo | concrete_reinforced | [0.666667,0.662745,0.619608] | 0.96 | Zona de separación de aire; BIM · Cimentaciones | 0.450754 | 0.450754 | 1 | 287.1 | 288.1 | F-WT3001 | ["WT3001A","WT3001B","WT3001C","WT3001D"] | [] | 9–9 / 9A–9A | ["25DC/25E1","25DC/25E2","25DC/25E4","25DC/2604","25DC/25E5","2473E"] | F-WT3001/Cimentación común de torres de refrigeración · pilar DZ9 18 | foundation | Geometría de fabricante; implantación absoluta provisional | WT3001A, WT3001B, WT3001C, WT3001D | Cimentaciones de equipos y pedestales del fabricante · revisión recibida 04/09/2026 | 25DC/25E1, 25DC/25E2, 25DC/25E4, 25DC/2604, 25DC/25E5, 2473E | 1 | 2 | 0.16 | Cotas relativas del dibujo. La equivalencia con un datum absoluto está pendiente. | Z del modelo = cota relativa + 1,10 m. Correspondencia provisional con 286,10 m; no es cota de obra confirmada. | Sección y contornos del fabricante; incidencias conservadas | 0.4 | 0.4 | Planta: −2,200 m. Secciones: fondo −2,000 m, losa superior −1,200 m; se adoptan secciones. / La última línea transversal presenta una discrepancia de 4 mm respecto a los ejes de pilares; se conserva la posición de cada contorno fuente.
Cimentación común de torres de refrigeración · pilar DZ9 19 | Parcela industrial Jinhong | Cimentación industrial | Cimentaciones de equipos y pedestales del fabricante · revisión recibida 04/09/2026 | 0.450754 | 0.450754 | 1 | 1.92 | 0.16 | process_plant | Zona de separación de aire | {"name":"Hormigón armado · clase pendiente de confirmar","status":"Clase no confirmada en la hoja de equipo","source":"Geometría de cimentación del fabricante; no se extrapola HA-30 de la nota de pedestales."} | {"documented":[{"label":"Extensión local X","value":0.4,"unit":"m","source":"25DC/25E1, 25DC/25E2, 25DC/25E4, 25DC/2604, 25DC/25E5, 2473E","status":"derivada del contorno CAD"},{"label":"Extensión local Y","value":0.4,"unit":"m","source":"25DC/25E1, 25DC/25E2, 25DC/25E4, 25DC/2604, 25DC/25E5, 2473E","status":"derivada del contorno CAD"},{"label":"Cota inferior relativa adoptada","value":1,"unit":"m","source":"9–9 / 9A–9A","status":"interpretación con conflicto conservado"},{"label":"Cota superior relativa adoptada","value":2,"unit":"m","source":"9–9 / 9A–9A","status":"documentada / separación por material"}],"geometry":[{"label":"Extensión de la malla en X","value":0.4507539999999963,"unit":"m","source":"Geometría releída del IFC; datum absoluto de proceso provisional","status":"derivado"},{"label":"Extensión de la malla en Y","value":0.45075400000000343,"unit":"m","source":"Geometría releída del IFC; datum absoluto de proceso provisional","status":"derivado"},{"label":"Extensión de la malla en Z","value":1.0,"unit":"m","source":"Geometría releída del IFC; datum absoluto de proceso provisional","status":"derivado"},{"label":"Cota inferior de visualización","value":287.1,"unit":"m","source":"Geometría releída del IFC; datum absoluto de proceso provisional","status":"derivado"},{"label":"Cota superior de visualización","value":288.1,"unit":"m","source":"Geometría releída del IFC; datum absoluto de proceso provisional","status":"derivado"}]} | {"documentId":"LHD2609-JG00100-20260904","title":"Cimentaciones de equipos y pedestales del fabricante · revisión recibida 04/09/2026","date":"2026-09-04","sheet":"9–9 / 9A–9A","fileName":"LHD2609-JG00100_20260904.dwg","revisionCaveat":"Fecha de revisión tomada del nombre recibido; cajetines internos mantienen 02/07/2026 y algunos textos de plantilla.","sourceFileSha256":"b42eb027b7bc0b14c38d1d13514f4899b58a732aa8d0ba2ccf10fa2fc3192890"} | provisional | ["Planta: −2,200 m. Secciones: fondo −2,000 m, losa superior −1,200 m; se adoptan secciones.","La última línea transversal presenta una discrepancia de 4 mm respecto a los ejes de pilares; se conserva la posición de cada contorno fuente."] | {"Cota inferior relativa (m)":1,"Cota superior relativa (m)":2,"Cero absoluto de visualización (m)":286.1,"Estado del cero absoluto":"Provisional","Criterio":"Las cotas relativas proceden del dibujo; la equivalencia absoluta no está confirmada."} | {"boundingBoxM":{"min":[39.784747,44.265409,2.1],"max":[40.235501,44.716163,3.1]},"extentsM":[0.450754,0.450754,1.0],"meshSurfaceM2":1.92,"meshVolumeM3":0.16,"closedSolid":true,"basis":"Magnitudes de las mallas representadas, no cantidades certificadas de obra, compra o fabricación. Las partes pueden compartir superficies; no se suman como un despiece de materiales."} | {"profileId":"concrete_reinforced","name":"Hormigón armado · gris natural","materialName":"Hormigón armado · clase pendiente de confirmar","physicalMaterialStatus":"Clase no confirmada en la hoja de equipo","physicalMaterialSource":"Geometría de cimentación del fabricante; no se extrapola HA-30 de la nota de pedestales.","appearanceStatus":"criterio_visual","appearanceBasis":"Interpretación visual del material documental; el acabado, tono y parámetros PBR no son una especificación contractual.","note":"La apariencia gráfica no modifica ni confirma la especificación física del material."} | {"elementId":"found_0904_55670f7eeef42f","ifcGuid":"0EbqO0ByPQavXB9PeU1bc5","ifcClass":"IfcFooting","buildingId":"process_plant","buildingName":"Zona de separación de aire","sourceDocumentId":"LHD2609-JG00100-20260904","sourceRepresentationKind":"foundation"} | {"layerId":"foundations","layerName":"Cimentaciones","role":"Cimentación industrial","basis":"Clasificación por función del elemento; no modifica las especificaciones documentales."} | {"profileId":"concrete_reinforced","name":"Hormigón armado · gris natural","status":"criterio_visual","basis":"Interpretación visual del material documental; el acabado, tono y parámetros PBR no son una especificación contractual.","physicalMaterialUnchanged":true} | 0.16 | Hormigón armado · clase pendiente de confirmar | Hormigón armado · gris natural | found_0904_55670f7eeef42f | Geometría de cimentación del fabricante; no se extrapola HA-30 de la nota de pedestales. | Clase no confirmada en la hoja de equipo | concrete_reinforced | [0.666667,0.662745,0.619608] | 0.96 | Zona de separación de aire; BIM · Cimentaciones | 0.450754 | 0.450754 | 1 | 287.1 | 288.1 | F-WT3001 | ["WT3001A","WT3001B","WT3001C","WT3001D"] | [] | 9–9 / 9A–9A | ["25DC/25E1","25DC/25E2","25DC/25E4","25DC/2604","25DC/25E5","2473E"] | F-WT3001/Cimentación común de torres de refrigeración · pilar DZ9 19 | foundation | Geometría de fabricante; implantación absoluta provisional | WT3001A, WT3001B, WT3001C, WT3001D | Cimentaciones de equipos y pedestales del fabricante · revisión recibida 04/09/2026 | 25DC/25E1, 25DC/25E2, 25DC/25E4, 25DC/2604, 25DC/25E5, 2473E | 1 | 2 | 0.16 | Cotas relativas del dibujo. La equivalencia con un datum absoluto está pendiente. | Z del modelo = cota relativa + 1,10 m. Correspondencia provisional con 286,10 m; no es cota de obra confirmada. | Sección y contornos del fabricante; incidencias conservadas | 0.4 | 0.4 | Planta: −2,200 m. Secciones: fondo −2,000 m, losa superior −1,200 m; se adoptan secciones. / La última línea transversal presenta una discrepancia de 4 mm respecto a los ejes de pilares; se conserva la posición de cada contorno fuente.
Cimentación común de torres de refrigeración · pilar DZ9 20 | Parcela industrial Jinhong | Cimentación industrial | Cimentaciones de equipos y pedestales del fabricante · revisión recibida 04/09/2026 | 0.450754 | 0.450754 | 1 | 1.92 | 0.16 | process_plant | Zona de separación de aire | {"name":"Hormigón armado · clase pendiente de confirmar","status":"Clase no confirmada en la hoja de equipo","source":"Geometría de cimentación del fabricante; no se extrapola HA-30 de la nota de pedestales."} | {"documented":[{"label":"Extensión local X","value":0.4,"unit":"m","source":"25DC/25E1, 25DC/25E2, 25DC/25E4, 25DC/2604, 25DC/25E5, 2473E","status":"derivada del contorno CAD"},{"label":"Extensión local Y","value":0.4,"unit":"m","source":"25DC/25E1, 25DC/25E2, 25DC/25E4, 25DC/2604, 25DC/25E5, 2473E","status":"derivada del contorno CAD"},{"label":"Cota inferior relativa adoptada","value":1,"unit":"m","source":"9–9 / 9A–9A","status":"interpretación con conflicto conservado"},{"label":"Cota superior relativa adoptada","value":2,"unit":"m","source":"9–9 / 9A–9A","status":"documentada / separación por material"}],"geometry":[{"label":"Extensión de la malla en X","value":0.4507539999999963,"unit":"m","source":"Geometría releída del IFC; datum absoluto de proceso provisional","status":"derivado"},{"label":"Extensión de la malla en Y","value":0.45075400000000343,"unit":"m","source":"Geometría releída del IFC; datum absoluto de proceso provisional","status":"derivado"},{"label":"Extensión de la malla en Z","value":1.0,"unit":"m","source":"Geometría releída del IFC; datum absoluto de proceso provisional","status":"derivado"},{"label":"Cota inferior de visualización","value":287.1,"unit":"m","source":"Geometría releída del IFC; datum absoluto de proceso provisional","status":"derivado"},{"label":"Cota superior de visualización","value":288.1,"unit":"m","source":"Geometría releída del IFC; datum absoluto de proceso provisional","status":"derivado"}]} | {"documentId":"LHD2609-JG00100-20260904","title":"Cimentaciones de equipos y pedestales del fabricante · revisión recibida 04/09/2026","date":"2026-09-04","sheet":"9–9 / 9A–9A","fileName":"LHD2609-JG00100_20260904.dwg","revisionCaveat":"Fecha de revisión tomada del nombre recibido; cajetines internos mantienen 02/07/2026 y algunos textos de plantilla.","sourceFileSha256":"b42eb027b7bc0b14c38d1d13514f4899b58a732aa8d0ba2ccf10fa2fc3192890"} | provisional | ["Planta: −2,200 m. Secciones: fondo −2,000 m, losa superior −1,200 m; se adoptan secciones.","La última línea transversal presenta una discrepancia de 4 mm respecto a los ejes de pilares; se conserva la posición de cada contorno fuente."] | {"Cota inferior relativa (m)":1,"Cota superior relativa (m)":2,"Cero absoluto de visualización (m)":286.1,"Estado del cero absoluto":"Provisional","Criterio":"Las cotas relativas proceden del dibujo; la equivalencia absoluta no está confirmada."} | {"boundingBoxM":{"min":[41.703696,44.001582,2.1],"max":[42.15445,44.452336,3.1]},"extentsM":[0.450754,0.450754,1.0],"meshSurfaceM2":1.92,"meshVolumeM3":0.16,"closedSolid":true,"basis":"Magnitudes de las mallas representadas, no cantidades certificadas de obra, compra o fabricación. Las partes pueden compartir superficies; no se suman como un despiece de materiales."} | {"profileId":"concrete_reinforced","name":"Hormigón armado · gris natural","materialName":"Hormigón armado · clase pendiente de confirmar","physicalMaterialStatus":"Clase no confirmada en la hoja de equipo","physicalMaterialSource":"Geometría de cimentación del fabricante; no se extrapola HA-30 de la nota de pedestales.","appearanceStatus":"criterio_visual","appearanceBasis":"Interpretación visual del material documental; el acabado, tono y parámetros PBR no son una especificación contractual.","note":"La apariencia gráfica no modifica ni confirma la especificación física del material."} | {"elementId":"found_0904_0f15bdeffb5062","ifcGuid":"0MgVk1a5XMUejw0uLlJh3r","ifcClass":"IfcFooting","buildingId":"process_plant","buildingName":"Zona de separación de aire","sourceDocumentId":"LHD2609-JG00100-20260904","sourceRepresentationKind":"foundation"} | {"layerId":"foundations","layerName":"Cimentaciones","role":"Cimentación industrial","basis":"Clasificación por función del elemento; no modifica las especificaciones documentales."} | {"profileId":"concrete_reinforced","name":"Hormigón armado · gris natural","status":"criterio_visual","basis":"Interpretación visual del material documental; el acabado, tono y parámetros PBR no son una especificación contractual.","physicalMaterialUnchanged":true} | 0.16 | Hormigón armado · clase pendiente de confirmar | Hormigón armado · gris natural | found_0904_0f15bdeffb5062 | Geometría de cimentación del fabricante; no se extrapola HA-30 de la nota de pedestales. | Clase no confirmada en la hoja de equipo | concrete_reinforced | [0.666667,0.662745,0.619608] | 0.96 | Zona de separación de aire; BIM · Cimentaciones | 0.450754 | 0.450754 | 1 | 287.1 | 288.1 | F-WT3001 | ["WT3001A","WT3001B","WT3001C","WT3001D"] | [] | 9–9 / 9A–9A | ["25DC/25E1","25DC/25E2","25DC/25E4","25DC/2604","25DC/25E5","2473E"] | F-WT3001/Cimentación común de torres de refrigeración · pilar DZ9 20 | foundation | Geometría de fabricante; implantación absoluta provisional | WT3001A, WT3001B, WT3001C, WT3001D | Cimentaciones de equipos y pedestales del fabricante · revisión recibida 04/09/2026 | 25DC/25E1, 25DC/25E2, 25DC/25E4, 25DC/2604, 25DC/25E5, 2473E | 1 | 2 | 0.16 | Cotas relativas del dibujo. La equivalencia con un datum absoluto está pendiente. | Z del modelo = cota relativa + 1,10 m. Correspondencia provisional con 286,10 m; no es cota de obra confirmada. | Sección y contornos del fabricante; incidencias conservadas | 0.4 | 0.4 | Planta: −2,200 m. Secciones: fondo −2,000 m, losa superior −1,200 m; se adoptan secciones. / La última línea transversal presenta una discrepancia de 4 mm respecto a los ejes de pilares; se conserva la posición de cada contorno fuente.
Cimentación común de torres de refrigeración · pilar DZ9 21 | Parcela industrial Jinhong | Cimentación industrial | Cimentaciones de equipos y pedestales del fabricante · revisión recibida 04/09/2026 | 0.450754 | 0.450754 | 1 | 1.92 | 0.16 | process_plant | Zona de separación de aire | {"name":"Hormigón armado · clase pendiente de confirmar","status":"Clase no confirmada en la hoja de equipo","source":"Geometría de cimentación del fabricante; no se extrapola HA-30 de la nota de pedestales."} | {"documented":[{"label":"Extensión local X","value":0.4,"unit":"m","source":"25DC/25E1, 25DC/25E2, 25DC/25E4, 25DC/2604, 25DC/25E5, 2473E","status":"derivada del contorno CAD"},{"label":"Extensión local Y","value":0.4,"unit":"m","source":"25DC/25E1, 25DC/25E2, 25DC/25E4, 25DC/2604, 25DC/25E5, 2473E","status":"derivada del contorno CAD"},{"label":"Cota inferior relativa adoptada","value":1,"unit":"m","source":"9–9 / 9A–9A","status":"interpretación con conflicto conservado"},{"label":"Cota superior relativa adoptada","value":2,"unit":"m","source":"9–9 / 9A–9A","status":"documentada / separación por material"}],"geometry":[{"label":"Extensión de la malla en X","value":0.4507539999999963,"unit":"m","source":"Geometría releída del IFC; datum absoluto de proceso provisional","status":"derivado"},{"label":"Extensión de la malla en Y","value":0.4507539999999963,"unit":"m","source":"Geometría releída del IFC; datum absoluto de proceso provisional","status":"derivado"},{"label":"Extensión de la malla en Z","value":1.0,"unit":"m","source":"Geometría releída del IFC; datum absoluto de proceso provisional","status":"derivado"},{"label":"Cota inferior de visualización","value":287.1,"unit":"m","source":"Geometría releída del IFC; datum absoluto de proceso provisional","status":"derivado"},{"label":"Cota superior de visualización","value":288.1,"unit":"m","source":"Geometría releída del IFC; datum absoluto de proceso provisional","status":"derivado"}]} | {"documentId":"LHD2609-JG00100-20260904","title":"Cimentaciones de equipos y pedestales del fabricante · revisión recibida 04/09/2026","date":"2026-09-04","sheet":"9–9 / 9A–9A","fileName":"LHD2609-JG00100_20260904.dwg","revisionCaveat":"Fecha de revisión tomada del nombre recibido; cajetines internos mantienen 02/07/2026 y algunos textos de plantilla.","sourceFileSha256":"b42eb027b7bc0b14c38d1d13514f4899b58a732aa8d0ba2ccf10fa2fc3192890"} | provisional | ["Planta: −2,200 m. Secciones: fondo −2,000 m, losa superior −1,200 m; se adoptan secciones.","La última línea transversal presenta una discrepancia de 4 mm respecto a los ejes de pilares; se conserva la posición de cada contorno fuente."] | {"Cota inferior relativa (m)":1,"Cota superior relativa (m)":2,"Cero absoluto de visualización (m)":286.1,"Estado del cero absoluto":"Provisional","Criterio":"Las cotas relativas proceden del dibujo; la equivalencia absoluta no está confirmada."} | {"boundingBoxM":{"min":[35.656364,42.67287,2.1],"max":[36.107118,43.123624,3.1]},"extentsM":[0.450754,0.450754,1.0],"meshSurfaceM2":1.920001,"meshVolumeM3":0.16,"closedSolid":true,"basis":"Magnitudes de las mallas representadas, no cantidades certificadas de obra, compra o fabricación. Las partes pueden compartir superficies; no se suman como un despiece de materiales."} | {"profileId":"concrete_reinforced","name":"Hormigón armado · gris natural","materialName":"Hormigón armado · clase pendiente de confirmar","physicalMaterialStatus":"Clase no confirmada en la hoja de equipo","physicalMaterialSource":"Geometría de cimentación del fabricante; no se extrapola HA-30 de la nota de pedestales.","appearanceStatus":"criterio_visual","appearanceBasis":"Interpretación visual del material documental; el acabado, tono y parámetros PBR no son una especificación contractual.","note":"La apariencia gráfica no modifica ni confirma la especificación física del material."} | {"elementId":"found_0904_3888b8a8668d2d","ifcGuid":"3X0subVoXQy8PLN5qTwiTO","ifcClass":"IfcFooting","buildingId":"process_plant","buildingName":"Zona de separación de aire","sourceDocumentId":"LHD2609-JG00100-20260904","sourceRepresentationKind":"foundation"} | {"layerId":"foundations","layerName":"Cimentaciones","role":"Cimentación industrial","basis":"Clasificación por función del elemento; no modifica las especificaciones documentales."} | {"profileId":"concrete_reinforced","name":"Hormigón armado · gris natural","status":"criterio_visual","basis":"Interpretación visual del material documental; el acabado, tono y parámetros PBR no son una especificación contractual.","physicalMaterialUnchanged":true} | 0.16 | Hormigón armado · clase pendiente de confirmar | Hormigón armado · gris natural | found_0904_3888b8a8668d2d | Geometría de cimentación del fabricante; no se extrapola HA-30 de la nota de pedestales. | Clase no confirmada en la hoja de equipo | concrete_reinforced | [0.666667,0.662745,0.619608] | 0.96 | Zona de separación de aire; BIM · Cimentaciones | 0.450754 | 0.450754 | 1 | 287.1 | 288.1 | F-WT3001 | ["WT3001A","WT3001B","WT3001C","WT3001D"] | [] | 9–9 / 9A–9A | ["25DC/25E1","25DC/25E2","25DC/25E4","25DC/2604","25DC/25E5","2473E"] | F-WT3001/Cimentación común de torres de refrigeración · pilar DZ9 21 | foundation | Geometría de fabricante; implantación absoluta provisional | WT3001A, WT3001B, WT3001C, WT3001D | Cimentaciones de equipos y pedestales del fabricante · revisión recibida 04/09/2026 | 25DC/25E1, 25DC/25E2, 25DC/25E4, 25DC/2604, 25DC/25E5, 2473E | 1 | 2 | 0.16 | Cotas relativas del dibujo. La equivalencia con un datum absoluto está pendiente. | Z del modelo = cota relativa + 1,10 m. Correspondencia provisional con 286,10 m; no es cota de obra confirmada. | Sección y contornos del fabricante; incidencias conservadas | 0.4 | 0.4 | Planta: −2,200 m. Secciones: fondo −2,000 m, losa superior −1,200 m; se adoptan secciones. / La última línea transversal presenta una discrepancia de 4 mm respecto a los ejes de pilares; se conserva la posición de cada contorno fuente.
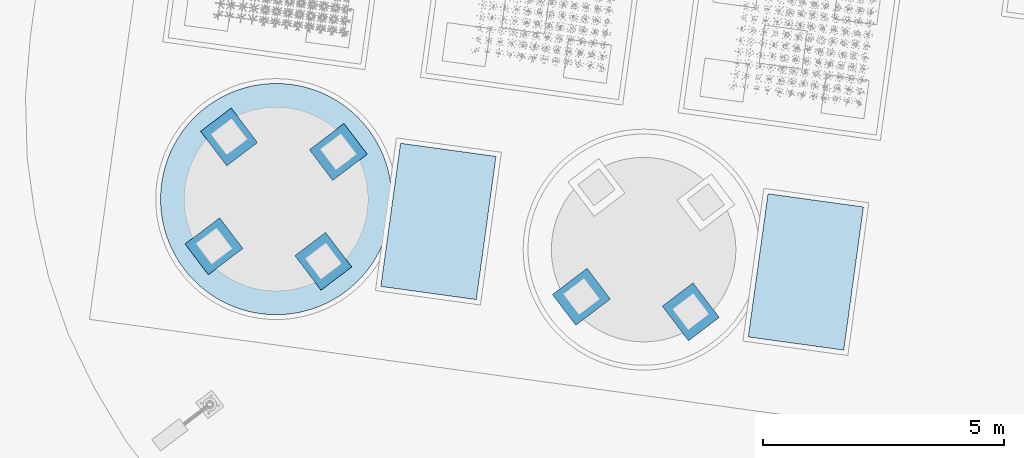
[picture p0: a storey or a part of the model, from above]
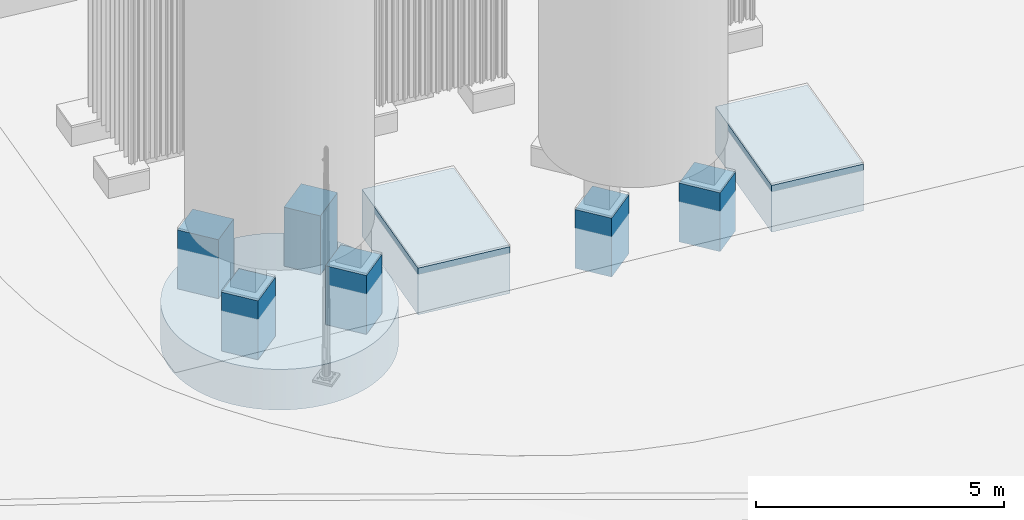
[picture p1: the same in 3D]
Properties of the parts of a building model (IFC4), part 73 of 134

# IfcFooting (214)
Name | In | Description = category = Categoria = Funcion | Document | ExtensionX (m) | ExtensionY (m) | ExtensionZ (m) | SuperficieDeLaMalla (m2) | VolumenGeometrico (m3) | buildingId | buildingName | material | dimensions | JH_InformacionBIM, source = DocumentoFuente | JH_InformacionBIM, status = EstadoDeInformacion | issues = IncidenciasPendientes | positioning = PosicionYEstado | geometryMetrics | materialAppearance | visualizationIdentity | classification | appearance | Volumen geométrico (m³) | JH_Trazabilidad, Material = name | Acabado de visualización = Acabado | Identificador | JH_EvidenciaDeMaterial, source | JH_EvidenciaDeMaterial, status | Perfil | ColorRGB | Rugosidad | Group | Extensión de la malla en X (m) | Extensión de la malla en Y (m) | Extensión de la malla en Z (m) = Espesor o altura real de sección (m) | Cota inferior de visualización (m) | Cota superior de visualización (m) | assemblyId = Conjunto de cimentación | equipmentIds | supportPositionIds | sectionRef = Sección de referencia | sourceCadHandles | stableElementKey | representationKind | geometryStatus | Equipos asociados | Documento de origen | Identificadores CAD de referencia | Cota inferior relativa (m) = Cota inferior relativa adoptada (m) | Cota superior relativa (m) = Cota superior relativa adoptada (m) | Área de planta (m²) | Referencia vertical | Implantación para visualización | Estado de la geometría | Extensión local X (m) | Extensión local Y (m) | Incidencias de origen
Cimentación común de torres de refrigeración · pilar DZ9 22 | Parcela industrial Jinhong | Cimentación industrial | Cimentaciones de equipos y pedestales del fabricante · revisión recibida 04/09/2026 | 0.450754 | 0.450754 | 1 | 1.92 | 0.16 | process_plant | Zona de separación de aire | {"name":"Hormigón armado · clase pendiente de confirmar","status":"Clase no confirmada en la hoja de equipo","source":"Geometría de cimentación del fabricante; no se extrapola HA-30 de la nota de pedestales."} | {"documented":[{"label":"Extensión local X","value":0.4,"unit":"m","source":"25DC/25E1, 25DC/25E2, 25DC/25E4, 25DC/2604, 25DC/25E5, 2473E","status":"derivada del contorno CAD"},{"label":"Extensión local Y","value":0.4,"unit":"m","source":"25DC/25E1, 25DC/25E2, 25DC/25E4, 25DC/2604, 25DC/25E5, 2473E","status":"derivada del contorno CAD"},{"label":"Cota inferior relativa adoptada","value":1,"unit":"m","source":"9–9 / 9A–9A","status":"interpretación con conflicto conservado"},{"label":"Cota superior relativa adoptada","value":2,"unit":"m","source":"9–9 / 9A–9A","status":"documentada / separación por material"}],"geometry":[{"label":"Extensión de la malla en X","value":0.45075400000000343,"unit":"m","source":"Geometría releída del IFC; datum absoluto de proceso provisional","status":"derivado"},{"label":"Extensión de la malla en Y","value":0.4507539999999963,"unit":"m","source":"Geometría releída del IFC; datum absoluto de proceso provisional","status":"derivado"},{"label":"Extensión de la malla en Z","value":1.0,"unit":"m","source":"Geometría releída del IFC; datum absoluto de proceso provisional","status":"derivado"},{"label":"Cota inferior de visualización","value":287.1,"unit":"m","source":"Geometría releída del IFC; datum absoluto de proceso provisional","status":"derivado"},{"label":"Cota superior de visualización","value":288.1,"unit":"m","source":"Geometría releída del IFC; datum absoluto de proceso provisional","status":"derivado"}]} | {"documentId":"LHD2609-JG00100-20260904","title":"Cimentaciones de equipos y pedestales del fabricante · revisión recibida 04/09/2026","date":"2026-09-04","sheet":"9–9 / 9A–9A","fileName":"LHD2609-JG00100_20260904.dwg","revisionCaveat":"Fecha de revisión tomada del nombre recibido; cajetines internos mantienen 02/07/2026 y algunos textos de plantilla.","sourceFileSha256":"b42eb027b7bc0b14c38d1d13514f4899b58a732aa8d0ba2ccf10fa2fc3192890"} | provisional | ["Planta: −2,200 m. Secciones: fondo −2,000 m, losa superior −1,200 m; se adoptan secciones.","La última línea transversal presenta una discrepancia de 4 mm respecto a los ejes de pilares; se conserva la posición de cada contorno fuente."] | {"Cota inferior relativa (m)":1,"Cota superior relativa (m)":2,"Cero absoluto de visualización (m)":286.1,"Estado del cero absoluto":"Provisional","Criterio":"Las cotas relativas proceden del dibujo; la equivalencia absoluta no está confirmada."} | {"boundingBoxM":{"min":[36.760973,42.521002,2.1],"max":[37.211727,42.971756,3.1]},"extentsM":[0.450754,0.450754,1.0],"meshSurfaceM2":1.920001,"meshVolumeM3":0.16,"closedSolid":true,"basis":"Magnitudes de las mallas representadas, no cantidades certificadas de obra, compra o fabricación. Las partes pueden compartir superficies; no se suman como un despiece de materiales."} | {"profileId":"concrete_reinforced","name":"Hormigón armado · gris natural","materialName":"Hormigón armado · clase pendiente de confirmar","physicalMaterialStatus":"Clase no confirmada en la hoja de equipo","physicalMaterialSource":"Geometría de cimentación del fabricante; no se extrapola HA-30 de la nota de pedestales.","appearanceStatus":"criterio_visual","appearanceBasis":"Interpretación visual del material documental; el acabado, tono y parámetros PBR no son una especificación contractual.","note":"La apariencia gráfica no modifica ni confirma la especificación física del material."} | {"elementId":"found_0904_b854d9c6850a08","ifcGuid":"1Qf83YS$vSkQR6FGg9KFJE","ifcClass":"IfcFooting","buildingId":"process_plant","buildingName":"Zona de separación de aire","sourceDocumentId":"LHD2609-JG00100-20260904","sourceRepresentationKind":"foundation"} | {"layerId":"foundations","layerName":"Cimentaciones","role":"Cimentación industrial","basis":"Clasificación por función del elemento; no modifica las especificaciones documentales."} | {"profileId":"concrete_reinforced","name":"Hormigón armado · gris natural","status":"criterio_visual","basis":"Interpretación visual del material documental; el acabado, tono y parámetros PBR no son una especificación contractual.","physicalMaterialUnchanged":true} | 0.16 | Hormigón armado · clase pendiente de confirmar | Hormigón armado · gris natural | found_0904_b854d9c6850a08 | Geometría de cimentación del fabricante; no se extrapola HA-30 de la nota de pedestales. | Clase no confirmada en la hoja de equipo | concrete_reinforced | [0.666667,0.662745,0.619608] | 0.96 | Zona de separación de aire; BIM · Cimentaciones | 0.450754 | 0.450754 | 1 | 287.1 | 288.1 | F-WT3001 | ["WT3001A","WT3001B","WT3001C","WT3001D"] | [] | 9–9 / 9A–9A | ["25DC/25E1","25DC/25E2","25DC/25E4","25DC/2604","25DC/25E5","2473E"] | F-WT3001/Cimentación común de torres de refrigeración · pilar DZ9 22 | foundation | Geometría de fabricante; implantación absoluta provisional | WT3001A, WT3001B, WT3001C, WT3001D | Cimentaciones de equipos y pedestales del fabricante · revisión recibida 04/09/2026 | 25DC/25E1, 25DC/25E2, 25DC/25E4, 25DC/2604, 25DC/25E5, 2473E | 1 | 2 | 0.16 | Cotas relativas del dibujo. La equivalencia con un datum absoluto está pendiente. | Z del modelo = cota relativa + 1,10 m. Correspondencia provisional con 286,10 m; no es cota de obra confirmada. | Sección y contornos del fabricante; incidencias conservadas | 0.4 | 0.4 | Planta: −2,200 m. Secciones: fondo −2,000 m, losa superior −1,200 m; se adoptan secciones. / La última línea transversal presenta una discrepancia de 4 mm respecto a los ejes de pilares; se conserva la posición de cada contorno fuente.
Cimentación común de torres de refrigeración · pilar DZ9 23 | Parcela industrial Jinhong | Cimentación industrial | Cimentaciones de equipos y pedestales del fabricante · revisión recibida 04/09/2026 | 0.450754 | 0.450754 | 1 | 1.92 | 0.16 | process_plant | Zona de separación de aire | {"name":"Hormigón armado · clase pendiente de confirmar","status":"Clase no confirmada en la hoja de equipo","source":"Geometría de cimentación del fabricante; no se extrapola HA-30 de la nota de pedestales."} | {"documented":[{"label":"Extensión local X","value":0.4,"unit":"m","source":"25DC/25E1, 25DC/25E2, 25DC/25E4, 25DC/2604, 25DC/25E5, 2473E","status":"derivada del contorno CAD"},{"label":"Extensión local Y","value":0.4,"unit":"m","source":"25DC/25E1, 25DC/25E2, 25DC/25E4, 25DC/2604, 25DC/25E5, 2473E","status":"derivada del contorno CAD"},{"label":"Cota inferior relativa adoptada","value":1,"unit":"m","source":"9–9 / 9A–9A","status":"interpretación con conflicto conservado"},{"label":"Cota superior relativa adoptada","value":2,"unit":"m","source":"9–9 / 9A–9A","status":"documentada / separación por material"}],"geometry":[{"label":"Extensión de la malla en X","value":0.4507539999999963,"unit":"m","source":"Geometría releída del IFC; datum absoluto de proceso provisional","status":"derivado"},{"label":"Extensión de la malla en Y","value":0.45075400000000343,"unit":"m","source":"Geometría releída del IFC; datum absoluto de proceso provisional","status":"derivado"},{"label":"Extensión de la malla en Z","value":1.0,"unit":"m","source":"Geometría releída del IFC; datum absoluto de proceso provisional","status":"derivado"},{"label":"Cota inferior de visualización","value":287.1,"unit":"m","source":"Geometría releída del IFC; datum absoluto de proceso provisional","status":"derivado"},{"label":"Cota superior de visualización","value":288.1,"unit":"m","source":"Geometría releída del IFC; datum absoluto de proceso provisional","status":"derivado"}]} | {"documentId":"LHD2609-JG00100-20260904","title":"Cimentaciones de equipos y pedestales del fabricante · revisión recibida 04/09/2026","date":"2026-09-04","sheet":"9–9 / 9A–9A","fileName":"LHD2609-JG00100_20260904.dwg","revisionCaveat":"Fecha de revisión tomada del nombre recibido; cajetines internos mantienen 02/07/2026 y algunos textos de plantilla.","sourceFileSha256":"b42eb027b7bc0b14c38d1d13514f4899b58a732aa8d0ba2ccf10fa2fc3192890"} | provisional | ["Planta: −2,200 m. Secciones: fondo −2,000 m, losa superior −1,200 m; se adoptan secciones.","La última línea transversal presenta una discrepancia de 4 mm respecto a los ejes de pilares; se conserva la posición de cada contorno fuente."] | {"Cota inferior relativa (m)":1,"Cota superior relativa (m)":2,"Cero absoluto de visualización (m)":286.1,"Estado del cero absoluto":"Provisional","Criterio":"Las cotas relativas proceden del dibujo; la equivalencia absoluta no está confirmada."} | {"boundingBoxM":{"min":[37.575313,42.409043,2.1],"max":[38.026067,42.859797,3.1]},"extentsM":[0.450754,0.450754,1.0],"meshSurfaceM2":1.92,"meshVolumeM3":0.16,"closedSolid":true,"basis":"Magnitudes de las mallas representadas, no cantidades certificadas de obra, compra o fabricación. Las partes pueden compartir superficies; no se suman como un despiece de materiales."} | {"profileId":"concrete_reinforced","name":"Hormigón armado · gris natural","materialName":"Hormigón armado · clase pendiente de confirmar","physicalMaterialStatus":"Clase no confirmada en la hoja de equipo","physicalMaterialSource":"Geometría de cimentación del fabricante; no se extrapola HA-30 de la nota de pedestales.","appearanceStatus":"criterio_visual","appearanceBasis":"Interpretación visual del material documental; el acabado, tono y parámetros PBR no son una especificación contractual.","note":"La apariencia gráfica no modifica ni confirma la especificación física del material."} | {"elementId":"found_0904_836c4a3d314078","ifcGuid":"1zv8PlW$bQcR6_UzzK5GTe","ifcClass":"IfcFooting","buildingId":"process_plant","buildingName":"Zona de separación de aire","sourceDocumentId":"LHD2609-JG00100-20260904","sourceRepresentationKind":"foundation"} | {"layerId":"foundations","layerName":"Cimentaciones","role":"Cimentación industrial","basis":"Clasificación por función del elemento; no modifica las especificaciones documentales."} | {"profileId":"concrete_reinforced","name":"Hormigón armado · gris natural","status":"criterio_visual","basis":"Interpretación visual del material documental; el acabado, tono y parámetros PBR no son una especificación contractual.","physicalMaterialUnchanged":true} | 0.16 | Hormigón armado · clase pendiente de confirmar | Hormigón armado · gris natural | found_0904_836c4a3d314078 | Geometría de cimentación del fabricante; no se extrapola HA-30 de la nota de pedestales. | Clase no confirmada en la hoja de equipo | concrete_reinforced | [0.666667,0.662745,0.619608] | 0.96 | Zona de separación de aire; BIM · Cimentaciones | 0.450754 | 0.450754 | 1 | 287.1 | 288.1 | F-WT3001 | ["WT3001A","WT3001B","WT3001C","WT3001D"] | [] | 9–9 / 9A–9A | ["25DC/25E1","25DC/25E2","25DC/25E4","25DC/2604","25DC/25E5","2473E"] | F-WT3001/Cimentación común de torres de refrigeración · pilar DZ9 23 | foundation | Geometría de fabricante; implantación absoluta provisional | WT3001A, WT3001B, WT3001C, WT3001D | Cimentaciones de equipos y pedestales del fabricante · revisión recibida 04/09/2026 | 25DC/25E1, 25DC/25E2, 25DC/25E4, 25DC/2604, 25DC/25E5, 2473E | 1 | 2 | 0.16 | Cotas relativas del dibujo. La equivalencia con un datum absoluto está pendiente. | Z del modelo = cota relativa + 1,10 m. Correspondencia provisional con 286,10 m; no es cota de obra confirmada. | Sección y contornos del fabricante; incidencias conservadas | 0.4 | 0.4 | Planta: −2,200 m. Secciones: fondo −2,000 m, losa superior −1,200 m; se adoptan secciones. / La última línea transversal presenta una discrepancia de 4 mm respecto a los ejes de pilares; se conserva la posición de cada contorno fuente.
Cimentación común de torres de refrigeración · pilar DZ9 24 | Parcela industrial Jinhong | Cimentación industrial | Cimentaciones de equipos y pedestales del fabricante · revisión recibida 04/09/2026 | 0.450754 | 0.450754 | 1 | 1.92 | 0.16 | process_plant | Zona de separación de aire | {"name":"Hormigón armado · clase pendiente de confirmar","status":"Clase no confirmada en la hoja de equipo","source":"Geometría de cimentación del fabricante; no se extrapola HA-30 de la nota de pedestales."} | {"documented":[{"label":"Extensión local X","value":0.4,"unit":"m","source":"25DC/25E1, 25DC/25E2, 25DC/25E4, 25DC/2604, 25DC/25E5, 2473E","status":"derivada del contorno CAD"},{"label":"Extensión local Y","value":0.4,"unit":"m","source":"25DC/25E1, 25DC/25E2, 25DC/25E4, 25DC/2604, 25DC/25E5, 2473E","status":"derivada del contorno CAD"},{"label":"Cota inferior relativa adoptada","value":1,"unit":"m","source":"9–9 / 9A–9A","status":"interpretación con conflicto conservado"},{"label":"Cota superior relativa adoptada","value":2,"unit":"m","source":"9–9 / 9A–9A","status":"documentada / separación por material"}],"geometry":[{"label":"Extensión de la malla en X","value":0.45075400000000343,"unit":"m","source":"Geometría releída del IFC; datum absoluto de proceso provisional","status":"derivado"},{"label":"Extensión de la malla en Y","value":0.4507539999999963,"unit":"m","source":"Geometría releída del IFC; datum absoluto de proceso provisional","status":"derivado"},{"label":"Extensión de la malla en Z","value":1.0,"unit":"m","source":"Geometría releída del IFC; datum absoluto de proceso provisional","status":"derivado"},{"label":"Cota inferior de visualización","value":287.1,"unit":"m","source":"Geometría releída del IFC; datum absoluto de proceso provisional","status":"derivado"},{"label":"Cota superior de visualización","value":288.1,"unit":"m","source":"Geometría releída del IFC; datum absoluto de proceso provisional","status":"derivado"}]} | {"documentId":"LHD2609-JG00100-20260904","title":"Cimentaciones de equipos y pedestales del fabricante · revisión recibida 04/09/2026","date":"2026-09-04","sheet":"9–9 / 9A–9A","fileName":"LHD2609-JG00100_20260904.dwg","revisionCaveat":"Fecha de revisión tomada del nombre recibido; cajetines internos mantienen 02/07/2026 y algunos textos de plantilla.","sourceFileSha256":"b42eb027b7bc0b14c38d1d13514f4899b58a732aa8d0ba2ccf10fa2fc3192890"} | provisional | ["Planta: −2,200 m. Secciones: fondo −2,000 m, losa superior −1,200 m; se adoptan secciones.","La última línea transversal presenta una discrepancia de 4 mm respecto a los ejes de pilares; se conserva la posición de cada contorno fuente."] | {"Cota inferior relativa (m)":1,"Cota superior relativa (m)":2,"Cero absoluto de visualización (m)":286.1,"Estado del cero absoluto":"Provisional","Criterio":"Las cotas relativas proceden del dibujo; la equivalencia absoluta no está confirmada."} | {"boundingBoxM":{"min":[39.493271,42.145352,2.1],"max":[39.944025,42.596106,3.1]},"extentsM":[0.450754,0.450754,1.0],"meshSurfaceM2":1.919999,"meshVolumeM3":0.16,"closedSolid":true,"basis":"Magnitudes de las mallas representadas, no cantidades certificadas de obra, compra o fabricación. Las partes pueden compartir superficies; no se suman como un despiece de materiales."} | {"profileId":"concrete_reinforced","name":"Hormigón armado · gris natural","materialName":"Hormigón armado · clase pendiente de confirmar","physicalMaterialStatus":"Clase no confirmada en la hoja de equipo","physicalMaterialSource":"Geometría de cimentación del fabricante; no se extrapola HA-30 de la nota de pedestales.","appearanceStatus":"criterio_visual","appearanceBasis":"Interpretación visual del material documental; el acabado, tono y parámetros PBR no son una especificación contractual.","note":"La apariencia gráfica no modifica ni confirma la especificación física del material."} | {"elementId":"found_0904_0e2be8a1815455","ifcGuid":"2EQ9hOhO5Kv8g9cQfeL4yF","ifcClass":"IfcFooting","buildingId":"process_plant","buildingName":"Zona de separación de aire","sourceDocumentId":"LHD2609-JG00100-20260904","sourceRepresentationKind":"foundation"} | {"layerId":"foundations","layerName":"Cimentaciones","role":"Cimentación industrial","basis":"Clasificación por función del elemento; no modifica las especificaciones documentales."} | {"profileId":"concrete_reinforced","name":"Hormigón armado · gris natural","status":"criterio_visual","basis":"Interpretación visual del material documental; el acabado, tono y parámetros PBR no son una especificación contractual.","physicalMaterialUnchanged":true} | 0.16 | Hormigón armado · clase pendiente de confirmar | Hormigón armado · gris natural | found_0904_0e2be8a1815455 | Geometría de cimentación del fabricante; no se extrapola HA-30 de la nota de pedestales. | Clase no confirmada en la hoja de equipo | concrete_reinforced | [0.666667,0.662745,0.619608] | 0.96 | Zona de separación de aire; BIM · Cimentaciones | 0.450754 | 0.450754 | 1 | 287.1 | 288.1 | F-WT3001 | ["WT3001A","WT3001B","WT3001C","WT3001D"] | [] | 9–9 / 9A–9A | ["25DC/25E1","25DC/25E2","25DC/25E4","25DC/2604","25DC/25E5","2473E"] | F-WT3001/Cimentación común de torres de refrigeración · pilar DZ9 24 | foundation | Geometría de fabricante; implantación absoluta provisional | WT3001A, WT3001B, WT3001C, WT3001D | Cimentaciones de equipos y pedestales del fabricante · revisión recibida 04/09/2026 | 25DC/25E1, 25DC/25E2, 25DC/25E4, 25DC/2604, 25DC/25E5, 2473E | 1 | 2 | 0.16 | Cotas relativas del dibujo. La equivalencia con un datum absoluto está pendiente. | Z del modelo = cota relativa + 1,10 m. Correspondencia provisional con 286,10 m; no es cota de obra confirmada. | Sección y contornos del fabricante; incidencias conservadas | 0.4 | 0.4 | Planta: −2,200 m. Secciones: fondo −2,000 m, losa superior −1,200 m; se adoptan secciones. / La última línea transversal presenta una discrepancia de 4 mm respecto a los ejes de pilares; se conserva la posición de cada contorno fuente.
Cimentación común de torres de refrigeración · pilar DZ9 25 | Parcela industrial Jinhong | Cimentación industrial | Cimentaciones de equipos y pedestales del fabricante · revisión recibida 04/09/2026 | 0.450754 | 0.450754 | 1 | 1.92 | 0.16 | process_plant | Zona de separación de aire | {"name":"Hormigón armado · clase pendiente de confirmar","status":"Clase no confirmada en la hoja de equipo","source":"Geometría de cimentación del fabricante; no se extrapola HA-30 de la nota de pedestales."} | {"documented":[{"label":"Extensión local X","value":0.4,"unit":"m","source":"25DC/25E1, 25DC/25E2, 25DC/25E4, 25DC/2604, 25DC/25E5, 2473E","status":"derivada del contorno CAD"},{"label":"Extensión local Y","value":0.4,"unit":"m","source":"25DC/25E1, 25DC/25E2, 25DC/25E4, 25DC/2604, 25DC/25E5, 2473E","status":"derivada del contorno CAD"},{"label":"Cota inferior relativa adoptada","value":1,"unit":"m","source":"9–9 / 9A–9A","status":"interpretación con conflicto conservado"},{"label":"Cota superior relativa adoptada","value":2,"unit":"m","source":"9–9 / 9A–9A","status":"documentada / separación por material"}],"geometry":[{"label":"Extensión de la malla en X","value":0.45075400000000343,"unit":"m","source":"Geometría releída del IFC; datum absoluto de proceso provisional","status":"derivado"},{"label":"Extensión de la malla en Y","value":0.4507539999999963,"unit":"m","source":"Geometría releída del IFC; datum absoluto de proceso provisional","status":"derivado"},{"label":"Extensión de la malla en Z","value":1.0,"unit":"m","source":"Geometría releída del IFC; datum absoluto de proceso provisional","status":"derivado"},{"label":"Cota inferior de visualización","value":287.1,"unit":"m","source":"Geometría releída del IFC; datum absoluto de proceso provisional","status":"derivado"},{"label":"Cota superior de visualización","value":288.1,"unit":"m","source":"Geometría releída del IFC; datum absoluto de proceso provisional","status":"derivado"}]} | {"documentId":"LHD2609-JG00100-20260904","title":"Cimentaciones de equipos y pedestales del fabricante · revisión recibida 04/09/2026","date":"2026-09-04","sheet":"9–9 / 9A–9A","fileName":"LHD2609-JG00100_20260904.dwg","revisionCaveat":"Fecha de revisión tomada del nombre recibido; cajetines internos mantienen 02/07/2026 y algunos textos de plantilla.","sourceFileSha256":"b42eb027b7bc0b14c38d1d13514f4899b58a732aa8d0ba2ccf10fa2fc3192890"} | provisional | ["Planta: −2,200 m. Secciones: fondo −2,000 m, losa superior −1,200 m; se adoptan secciones.","La última línea transversal presenta una discrepancia de 4 mm respecto a los ejes de pilares; se conserva la posición de cada contorno fuente."] | {"Cota inferior relativa (m)":1,"Cota superior relativa (m)":2,"Cero absoluto de visualización (m)":286.1,"Estado del cero absoluto":"Provisional","Criterio":"Las cotas relativas proceden del dibujo; la equivalencia absoluta no está confirmada."} | {"boundingBoxM":{"min":[41.41222,41.881525,2.1],"max":[41.862974,42.332279,3.1]},"extentsM":[0.450754,0.450754,1.0],"meshSurfaceM2":1.92,"meshVolumeM3":0.16,"closedSolid":true,"basis":"Magnitudes de las mallas representadas, no cantidades certificadas de obra, compra o fabricación. Las partes pueden compartir superficies; no se suman como un despiece de materiales."} | {"profileId":"concrete_reinforced","name":"Hormigón armado · gris natural","materialName":"Hormigón armado · clase pendiente de confirmar","physicalMaterialStatus":"Clase no confirmada en la hoja de equipo","physicalMaterialSource":"Geometría de cimentación del fabricante; no se extrapola HA-30 de la nota de pedestales.","appearanceStatus":"criterio_visual","appearanceBasis":"Interpretación visual del material documental; el acabado, tono y parámetros PBR no son una especificación contractual.","note":"La apariencia gráfica no modifica ni confirma la especificación física del material."} | {"elementId":"found_0904_ee9ea5a104f3a0","ifcGuid":"00dmmqGZHM1h7Hwfs1SZZA","ifcClass":"IfcFooting","buildingId":"process_plant","buildingName":"Zona de separación de aire","sourceDocumentId":"LHD2609-JG00100-20260904","sourceRepresentationKind":"foundation"} | {"layerId":"foundations","layerName":"Cimentaciones","role":"Cimentación industrial","basis":"Clasificación por función del elemento; no modifica las especificaciones documentales."} | {"profileId":"concrete_reinforced","name":"Hormigón armado · gris natural","status":"criterio_visual","basis":"Interpretación visual del material documental; el acabado, tono y parámetros PBR no son una especificación contractual.","physicalMaterialUnchanged":true} | 0.16 | Hormigón armado · clase pendiente de confirmar | Hormigón armado · gris natural | found_0904_ee9ea5a104f3a0 | Geometría de cimentación del fabricante; no se extrapola HA-30 de la nota de pedestales. | Clase no confirmada en la hoja de equipo | concrete_reinforced | [0.666667,0.662745,0.619608] | 0.96 | Zona de separación de aire; BIM · Cimentaciones | 0.450754 | 0.450754 | 1 | 287.1 | 288.1 | F-WT3001 | ["WT3001A","WT3001B","WT3001C","WT3001D"] | [] | 9–9 / 9A–9A | ["25DC/25E1","25DC/25E2","25DC/25E4","25DC/2604","25DC/25E5","2473E"] | F-WT3001/Cimentación común de torres de refrigeración · pilar DZ9 25 | foundation | Geometría de fabricante; implantación absoluta provisional | WT3001A, WT3001B, WT3001C, WT3001D | Cimentaciones de equipos y pedestales del fabricante · revisión recibida 04/09/2026 | 25DC/25E1, 25DC/25E2, 25DC/25E4, 25DC/2604, 25DC/25E5, 2473E | 1 | 2 | 0.16 | Cotas relativas del dibujo. La equivalencia con un datum absoluto está pendiente. | Z del modelo = cota relativa + 1,10 m. Correspondencia provisional con 286,10 m; no es cota de obra confirmada. | Sección y contornos del fabricante; incidencias conservadas | 0.4 | 0.4 | Planta: −2,200 m. Secciones: fondo −2,000 m, losa superior −1,200 m; se adoptan secciones. / La última línea transversal presenta una discrepancia de 4 mm respecto a los ejes de pilares; se conserva la posición de cada contorno fuente.
Base de bombas y dosificación · cuerpo de hormigón | Parcela industrial Jinhong | Cimentación industrial | Cimentaciones de equipos y pedestales del fabricante · revisión recibida 04/09/2026 | 6.38058 | 2.57816 | 1.15 | 39.985 | 12.4775 | process_plant | Zona de separación de aire | {"name":"Hormigón armado · clase pendiente de confirmar","status":"Clase no confirmada en la hoja de equipo","source":"Geometría de cimentación del fabricante; no se extrapola HA-30 de la nota de pedestales."} | {"documented":[{"label":"Extensión local X","value":6.2,"unit":"m","source":"26B8/26BE, 24851","status":"derivada del contorno CAD"},{"label":"Extensión local Y","value":1.75,"unit":"m","source":"26B8/26BE, 24851","status":"derivada del contorno CAD"},{"label":"Cota inferior relativa adoptada","value":-1,"unit":"m","source":"10–10","status":"documentada"},{"label":"Cota superior relativa adoptada","value":0.15000000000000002,"unit":"m","source":"10–10","status":"documentada / separación por material"}],"geometry":[{"label":"Extensión de la malla en X","value":6.380578,"unit":"m","source":"Geometría releída del IFC; datum absoluto de proceso provisional","status":"derivado"},{"label":"Extensión de la malla en Y","value":2.578156,"unit":"m","source":"Geometría releída del IFC; datum absoluto de proceso provisional","status":"derivado"},{"label":"Extensión de la malla en Z","value":1.15,"unit":"m","source":"Geometría releída del IFC; datum absoluto de proceso provisional","status":"derivado"},{"label":"Cota inferior de visualización","value":285.1,"unit":"m","source":"Geometría releída del IFC; datum absoluto de proceso provisional","status":"derivado"},{"label":"Cota superior de visualización","value":286.25,"unit":"m","source":"Geometría releída del IFC; datum absoluto de proceso provisional","status":"derivado"}]} | {"documentId":"LHD2609-JG00100-20260904","title":"Cimentaciones de equipos y pedestales del fabricante · revisión recibida 04/09/2026","date":"2026-09-04","sheet":"10–10","fileName":"LHD2609-JG00100_20260904.dwg","revisionCaveat":"Fecha de revisión tomada del nombre recibido; cajetines internos mantienen 02/07/2026 y algunos textos de plantilla.","sourceFileSha256":"b42eb027b7bc0b14c38d1d13514f4899b58a732aa8d0ba2ccf10fa2fc3192890"} | provisional | [] | {"Cota inferior relativa (m)":-1,"Cota superior relativa (m)":0.15000000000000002,"Cero absoluto de visualización (m)":286.1,"Estado del cero absoluto":"Provisional","Criterio":"Las cotas relativas proceden del dibujo; la equivalencia absoluta no está confirmada."} | {"boundingBoxM":{"min":[36.424623,55.510243,0.1],"max":[42.805201,58.088399,1.25]},"extentsM":[6.380578,2.578156,1.15],"meshSurfaceM2":39.985001,"meshVolumeM3":12.4775,"closedSolid":true,"basis":"Magnitudes de las mallas representadas, no cantidades certificadas de obra, compra o fabricación. Las partes pueden compartir superficies; no se suman como un despiece de materiales."} | {"profileId":"concrete_reinforced","name":"Hormigón armado · gris natural","materialName":"Hormigón armado · clase pendiente de confirmar","physicalMaterialStatus":"Clase no confirmada en la hoja de equipo","physicalMaterialSource":"Geometría de cimentación del fabricante; no se extrapola HA-30 de la nota de pedestales.","appearanceStatus":"criterio_visual","appearanceBasis":"Interpretación visual del material documental; el acabado, tono y parámetros PBR no son una especificación contractual.","note":"La apariencia gráfica no modifica ni confirma la especificación física del material."} | {"elementId":"found_0904_931d97c2f216a1","ifcGuid":"2EEY1MvQ5S4x1n5bTeMdOU","ifcClass":"IfcFooting","buildingId":"process_plant","buildingName":"Zona de separación de aire","sourceDocumentId":"LHD2609-JG00100-20260904","sourceRepresentationKind":"foundation"} | {"layerId":"foundations","layerName":"Cimentaciones","role":"Cimentación industrial","basis":"Clasificación por función del elemento; no modifica las especificaciones documentales."} | {"profileId":"concrete_reinforced","name":"Hormigón armado · gris natural","status":"criterio_visual","basis":"Interpretación visual del material documental; el acabado, tono y parámetros PBR no son una especificación contractual.","physicalMaterialUnchanged":true} | 12.4775 | Hormigón armado · clase pendiente de confirmar | Hormigón armado · gris natural | found_0904_931d97c2f216a1 | Geometría de cimentación del fabricante; no se extrapola HA-30 de la nota de pedestales. | Clase no confirmada en la hoja de equipo | concrete_reinforced | [0.666667,0.662745,0.619608] | 0.96 | Zona de separación de aire; BIM · Cimentaciones | 6.38058 | 2.57816 | 1.15 | 285.1 | 286.25 | F-SKID | ["PUMPS-DOSING-PLAN"] | [] | 10–10 | ["26B8/26BE","24851"] | F-SKID/Base de bombas y dosificación · cuerpo de hormigón | foundation | Geometría de fabricante; implantación absoluta provisional | PUMPS-DOSING-PLAN | Cimentaciones de equipos y pedestales del fabricante · revisión recibida 04/09/2026 | 26B8/26BE, 24851 | -1 | 0.15 | 10.85 | Cotas relativas del dibujo. La equivalencia con un datum absoluto está pendiente. | Z del modelo = cota relativa + 1,10 m. Correspondencia provisional con 286,10 m; no es cota de obra confirmada. | Contornos y sección documentados por el fabricante | 6.2 | 1.75
Base de la caseta de analizadores · cuerpo de hormigón | Parcela industrial Jinhong | Cimentación industrial | Cimentaciones de equipos y pedestales del fabricante · revisión recibida 04/09/2026 | 4.34409 | 3.31872 | 1.2 | 38.72 | 13.44 | process_plant | Zona de separación de aire | {"name":"Hormigón armado · clase pendiente de confirmar","status":"Clase no confirmada en la hoja de equipo","source":"Geometría de cimentación del fabricante; no se extrapola HA-30 de la nota de pedestales."} | {"documented":[{"label":"Extensión local X","value":4.0,"unit":"m","source":"26CA, 24873","status":"derivada del contorno CAD"},{"label":"Extensión local Y","value":2.8,"unit":"m","source":"26CA, 24873","status":"derivada del contorno CAD"},{"label":"Cota inferior relativa adoptada","value":-1,"unit":"m","source":"20–20","status":"documentada"},{"label":"Cota superior relativa adoptada","value":0.2,"unit":"m","source":"20–20","status":"documentada / separación por material"}],"geometry":[{"label":"Extensión de la malla en X","value":4.344093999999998,"unit":"m","source":"Geometría releída del IFC; datum absoluto de proceso provisional","status":"derivado"},{"label":"Extensión de la malla en Y","value":3.318722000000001,"unit":"m","source":"Geometría releída del IFC; datum absoluto de proceso provisional","status":"derivado"},{"label":"Extensión de la malla en Z","value":1.2,"unit":"m","source":"Geometría releída del IFC; datum absoluto de proceso provisional","status":"derivado"},{"label":"Cota inferior de visualización","value":285.1,"unit":"m","source":"Geometría releída del IFC; datum absoluto de proceso provisional","status":"derivado"},{"label":"Cota superior de visualización","value":286.3,"unit":"m","source":"Geometría releída del IFC; datum absoluto de proceso provisional","status":"derivado"}]} | {"documentId":"LHD2609-JG00100-20260904","title":"Cimentaciones de equipos y pedestales del fabricante · revisión recibida 04/09/2026","date":"2026-09-04","sheet":"20–20","fileName":"LHD2609-JG00100_20260904.dwg","revisionCaveat":"Fecha de revisión tomada del nombre recibido; cajetines internos mantienen 02/07/2026 y algunos textos de plantilla.","sourceFileSha256":"b42eb027b7bc0b14c38d1d13514f4899b58a732aa8d0ba2ccf10fa2fc3192890"} | provisional | [] | {"Cota inferior relativa (m)":-1,"Cota superior relativa (m)":0.2,"Cero absoluto de visualización (m)":286.1,"Estado del cero absoluto":"Provisional","Criterio":"Las cotas relativas proceden del dibujo; la equivalencia absoluta no está confirmada."} | {"boundingBoxM":{"min":[43.39708,38.97836,0.1],"max":[47.741174,42.297082,1.3]},"extentsM":[4.344094,3.318722,1.2],"meshSurfaceM2":38.72,"meshVolumeM3":13.44,"closedSolid":true,"basis":"Magnitudes de las mallas representadas, no cantidades certificadas de obra, compra o fabricación. Las partes pueden compartir superficies; no se suman como un despiece de materiales."} | {"profileId":"concrete_reinforced","name":"Hormigón armado · gris natural","materialName":"Hormigón armado · clase pendiente de confirmar","physicalMaterialStatus":"Clase no confirmada en la hoja de equipo","physicalMaterialSource":"Geometría de cimentación del fabricante; no se extrapola HA-30 de la nota de pedestales.","appearanceStatus":"criterio_visual","appearanceBasis":"Interpretación visual del material documental; el acabado, tono y parámetros PBR no son una especificación contractual.","note":"La apariencia gráfica no modifica ni confirma la especificación física del material."} | {"elementId":"found_0904_2945d17712b119","ifcGuid":"3k5UbbfgDJExzcqxLnfzwX","ifcClass":"IfcFooting","buildingId":"process_plant","buildingName":"Zona de separación de aire","sourceDocumentId":"LHD2609-JG00100-20260904","sourceRepresentationKind":"foundation"} | {"layerId":"foundations","layerName":"Cimentaciones","role":"Cimentación industrial","basis":"Clasificación por función del elemento; no modifica las especificaciones documentales."} | {"profileId":"concrete_reinforced","name":"Hormigón armado · gris natural","status":"criterio_visual","basis":"Interpretación visual del material documental; el acabado, tono y parámetros PBR no son una especificación contractual.","physicalMaterialUnchanged":true} | 13.44 | Hormigón armado · clase pendiente de confirmar | Hormigón armado · gris natural | found_0904_2945d17712b119 | Geometría de cimentación del fabricante; no se extrapola HA-30 de la nota de pedestales. | Clase no confirmada en la hoja de equipo | concrete_reinforced | [0.666667,0.662745,0.619608] | 0.96 | Zona de separación de aire; BIM · Cimentaciones | 4.34409 | 3.31872 | 1.2 | 285.1 | 286.3 | F-ANALYSIS | ["ANALYSIS-CABIN"] | [] | 20–20 | ["26CA","24873"] | F-ANALYSIS/Base de la caseta de analizadores · cuerpo de hormigón | foundation | Geometría de fabricante; implantación absoluta provisional | ANALYSIS-CABIN | Cimentaciones de equipos y pedestales del fabricante · revisión recibida 04/09/2026 | 26CA, 24873 | -1 | 0.2 | 11.2 | Cotas relativas del dibujo. La equivalencia con un datum absoluto está pendiente. | Z del modelo = cota relativa + 1,10 m. Correspondencia provisional con 286,10 m; no es cota de obra confirmada. | Contornos y sección documentados por el fabricante | 4 | 2.8
Cimentación y plataforma del módulo LV-CONTAINER · cuerpo de hormigón | Parcela industrial Jinhong | Cimentación industrial | Cimentaciones de equipos y pedestales del fabricante · revisión recibida 04/09/2026 | 6.07828 | 11.8674 | 1 | 135.703 | 51.9263 | process_plant | Zona de separación de aire | {"name":"Hormigón armado · clase pendiente de confirmar","status":"Clase no confirmada en la hoja de equipo","source":"Geometría de cimentación del fabricante; no se extrapola HA-30 de la nota de pedestales."} | {"documented":[{"label":"Extensión local X","value":4.575,"unit":"m","source":"55EB/55F1, 1DB82, 1DE55","status":"derivada del contorno CAD"},{"label":"Extensión local Y","value":11.35,"unit":"m","source":"55EB/55F1, 1DB82, 1DE55","status":"derivada del contorno CAD"},{"label":"Cota inferior relativa adoptada","value":-1,"unit":"m","source":"13–13","status":"interpretación con conflicto conservado"},{"label":"Cota superior relativa adoptada","value":0,"unit":"m","source":"13–13","status":"documentada / separación por material"}],"geometry":[{"label":"Extensión de la malla en X","value":6.078279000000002,"unit":"m","source":"Geometría releída del IFC; datum absoluto de proceso provisional","status":"derivado"},{"label":"Extensión de la malla en Y","value":11.867361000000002,"unit":"m","source":"Geometría releída del IFC; datum absoluto de proceso provisional","status":"derivado"},{"label":"Extensión de la malla en Z","value":1.0,"unit":"m","source":"Geometría releída del IFC; datum absoluto de proceso provisional","status":"derivado"},{"label":"Cota inferior de visualización","value":285.1,"unit":"m","source":"Geometría releída del IFC; datum absoluto de proceso provisional","status":"derivado"},{"label":"Cota superior de visualización","value":286.1,"unit":"m","source":"Geometría releída del IFC; datum absoluto de proceso provisional","status":"derivado"}]} | {"documentId":"LHD2609-JG00100-20260904","title":"Cimentaciones de equipos y pedestales del fabricante · revisión recibida 04/09/2026","date":"2026-09-04","sheet":"13–13","fileName":"LHD2609-JG00100_20260904.dwg","revisionCaveat":"Fecha de revisión tomada del nombre recibido; cajetines internos mantienen 02/07/2026 y algunos textos de plantilla.","sourceFileSha256":"b42eb027b7bc0b14c38d1d13514f4899b58a732aa8d0ba2ccf10fa2fc3192890"} | provisional | ["La planta general y algunos croquis de apoyo muestran dimensiones transversales distintas. Se usan el contorno de cimentación y los centros de pilares de la implantación general; sección de viga VC1 400 × 400 mm y vuelo a 1050 mm del eje según detalle.","La capa de mortero sobre la losa no tiene una referencia vertical inequívoca; no se duplica una capa independiente en esa losa."] | {"Cota inferior relativa (m)":-1,"Cota superior relativa (m)":0,"Cero absoluto de visualización (m)":286.1,"Estado del cero absoluto":"Provisional","Criterio":"Las cotas relativas proceden del dibujo; la equivalencia absoluta no está confirmada."} | {"boundingBoxM":{"min":[38.42586,72.490174,0.1],"max":[44.504139,84.357535,1.1]},"extentsM":[6.078279,11.867361,1.0],"meshSurfaceM2":135.702501,"meshVolumeM3":51.92625,"closedSolid":true,"basis":"Magnitudes de las mallas representadas, no cantidades certificadas de obra, compra o fabricación. Las partes pueden compartir superficies; no se suman como un despiece de materiales."} | {"profileId":"concrete_reinforced","name":"Hormigón armado · gris natural","materialName":"Hormigón armado · clase pendiente de confirmar","physicalMaterialStatus":"Clase no confirmada en la hoja de equipo","physicalMaterialSource":"Geometría de cimentación del fabricante; no se extrapola HA-30 de la nota de pedestales.","appearanceStatus":"criterio_visual","appearanceBasis":"Interpretación visual del material documental; el acabado, tono y parámetros PBR no son una especificación contractual.","note":"La apariencia gráfica no modifica ni confirma la especificación física del material."} | {"elementId":"found_0904_6624999f1865f2","ifcGuid":"0_aVAz2iDLeu7xk3rAjyZi","ifcClass":"IfcFooting","buildingId":"process_plant","buildingName":"Zona de separación de aire","sourceDocumentId":"LHD2609-JG00100-20260904","sourceRepresentationKind":"foundation"} | {"layerId":"foundations","layerName":"Cimentaciones","role":"Cimentación industrial","basis":"Clasificación por función del elemento; no modifica las especificaciones documentales."} | {"profileId":"concrete_reinforced","name":"Hormigón armado · gris natural","status":"criterio_visual","basis":"Interpretación visual del material documental; el acabado, tono y parámetros PBR no son una especificación contractual.","physicalMaterialUnchanged":true} | 51.9263 | Hormigón armado · clase pendiente de confirmar | Hormigón armado · gris natural | found_0904_6624999f1865f2 | Geometría de cimentación del fabricante; no se extrapola HA-30 de la nota de pedestales. | Clase no confirmada en la hoja de equipo | concrete_reinforced | [0.666667,0.662745,0.619608] | 0.96 | Zona de separación de aire; BIM · Cimentaciones | 6.07828 | 11.8674 | 1 | 285.1 | 286.1 | F-LV-CONTAINER | ["LV-CONTAINER"] | [] | 13–13 | ["55EB/55F1","1DB82","1DE55"] | F-LV-CONTAINER/Cimentación y plataforma del módulo LV-CONTAINER · cuerpo de hormigón | foundation | Geometría de fabricante; implantación absoluta provisional | LV-CONTAINER | Cimentaciones de equipos y pedestales del fabricante · revisión recibida 04/09/2026 | 55EB/55F1, 1DB82, 1DE55 | -1 | 0 | 51.9263 | Cotas relativas del dibujo. La equivalencia con un datum absoluto está pendiente. | Z del modelo = cota relativa + 1,10 m. Correspondencia provisional con 286,10 m; no es cota de obra confirmada. | Sección y contornos del fabricante; incidencias conservadas | 4.575 | 11.35 | La planta general y algunos croquis de apoyo muestran dimensiones transversales distintas. Se usan el contorno de cimentación y los centros de pilares de la implantación general; sección de viga VC1 400 × 400 mm y vuelo a 1050 mm del eje según detalle. / La capa de mortero sobre la losa no tiene una referencia vertical inequívoca; no se duplica una capa independiente en esa losa.
Cimentación y plataforma del módulo LV-CONTAINER · pilar KZ1 01 | Parcela industrial Jinhong | Cimentación industrial | Cimentaciones de equipos y pedestales del fabricante · revisión recibida 04/09/2026 | 0.450754 | 0.450754 | 1.1 | 2.08 | 0.176 | process_plant | Zona de separación de aire | {"name":"Hormigón armado · clase pendiente de confirmar","status":"Clase no confirmada en la hoja de equipo","source":"Geometría de cimentación del fabricante; no se extrapola HA-30 de la nota de pedestales."} | {"documented":[{"label":"Extensión local X","value":0.4,"unit":"m","source":"55EB/55F1, 1DB82, 1DE55","status":"derivada del contorno CAD"},{"label":"Extensión local Y","value":0.4,"unit":"m","source":"55EB/55F1, 1DB82, 1DE55","status":"derivada del contorno CAD"},{"label":"Cota inferior relativa adoptada","value":0,"unit":"m","source":"13–13","status":"interpretación con conflicto conservado"},{"label":"Cota superior relativa adoptada","value":1.1,"unit":"m","source":"13–13","status":"documentada / separación por material"}],"geometry":[{"label":"Extensión de la malla en X","value":0.45075400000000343,"unit":"m","source":"Geometría releída del IFC; datum absoluto de proceso provisional","status":"derivado"},{"label":"Extensión de la malla en Y","value":0.45075400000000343,"unit":"m","source":"Geometría releída del IFC; datum absoluto de proceso provisional","status":"derivado"},{"label":"Extensión de la malla en Z","value":1.1,"unit":"m","source":"Geometría releída del IFC; datum absoluto de proceso provisional","status":"derivado"},{"label":"Cota inferior de visualización","value":286.1,"unit":"m","source":"Geometría releída del IFC; datum absoluto de proceso provisional","status":"derivado"},{"label":"Cota superior de visualización","value":287.2,"unit":"m","source":"Geometría releída del IFC; datum absoluto de proceso provisional","status":"derivado"}]} | {"documentId":"LHD2609-JG00100-20260904","title":"Cimentaciones de equipos y pedestales del fabricante · revisión recibida 04/09/2026","date":"2026-09-04","sheet":"13–13","fileName":"LHD2609-JG00100_20260904.dwg","revisionCaveat":"Fecha de revisión tomada del nombre recibido; cajetines internos mantienen 02/07/2026 y algunos textos de plantilla.","sourceFileSha256":"b42eb027b7bc0b14c38d1d13514f4899b58a732aa8d0ba2ccf10fa2fc3192890"} | provisional | ["La planta general y algunos croquis de apoyo muestran dimensiones transversales distintas. Se usan el contorno de cimentación y los centros de pilares de la implantación general; sección de viga VC1 400 × 400 mm y vuelo a 1050 mm del eje según detalle.","La capa de mortero sobre la losa no tiene una referencia vertical inequívoca; no se duplica una capa independiente en esa losa."] | {"Cota inferior relativa (m)":0,"Cota superior relativa (m)":1.1,"Cero absoluto de visualización (m)":286.1,"Estado del cero absoluto":"Provisional","Criterio":"Las cotas relativas proceden del dibujo; la equivalencia absoluta no está confirmada."} | {"boundingBoxM":{"min":[42.305609,72.82824,1.1],"max":[42.756363,73.278994,2.2]},"extentsM":[0.450754,0.450754,1.1],"meshSurfaceM2":2.080001,"meshVolumeM3":0.176,"closedSolid":true,"basis":"Magnitudes de las mallas representadas, no cantidades certificadas de obra, compra o fabricación. Las partes pueden compartir superficies; no se suman como un despiece de materiales."} | {"profileId":"concrete_reinforced","name":"Hormigón armado · gris natural","materialName":"Hormigón armado · clase pendiente de confirmar","physicalMaterialStatus":"Clase no confirmada en la hoja de equipo","physicalMaterialSource":"Geometría de cimentación del fabricante; no se extrapola HA-30 de la nota de pedestales.","appearanceStatus":"criterio_visual","appearanceBasis":"Interpretación visual del material documental; el acabado, tono y parámetros PBR no son una especificación contractual.","note":"La apariencia gráfica no modifica ni confirma la especificación física del material."} | {"elementId":"found_0904_12e1ff91ca7419","ifcGuid":"07kmPCqHDRzQFyULDt78_H","ifcClass":"IfcFooting","buildingId":"process_plant","buildingName":"Zona de separación de aire","sourceDocumentId":"LHD2609-JG00100-20260904","sourceRepresentationKind":"foundation"} | {"layerId":"foundations","layerName":"Cimentaciones","role":"Cimentación industrial","basis":"Clasificación por función del elemento; no modifica las especificaciones documentales."} | {"profileId":"concrete_reinforced","name":"Hormigón armado · gris natural","status":"criterio_visual","basis":"Interpretación visual del material documental; el acabado, tono y parámetros PBR no son una especificación contractual.","physicalMaterialUnchanged":true} | 0.176 | Hormigón armado · clase pendiente de confirmar | Hormigón armado · gris natural | found_0904_12e1ff91ca7419 | Geometría de cimentación del fabricante; no se extrapola HA-30 de la nota de pedestales. | Clase no confirmada en la hoja de equipo | concrete_reinforced | [0.666667,0.662745,0.619608] | 0.96 | Zona de separación de aire; BIM · Cimentaciones | 0.450754 | 0.450754 | 1.1 | 286.1 | 287.2 | F-LV-CONTAINER | ["LV-CONTAINER"] | [] | 13–13 | ["55EB/55F1","1DB82","1DE55"] | F-LV-CONTAINER/Cimentación y plataforma del módulo LV-CONTAINER · pilar KZ1 01 | foundation | Geometría de fabricante; implantación absoluta provisional | LV-CONTAINER | Cimentaciones de equipos y pedestales del fabricante · revisión recibida 04/09/2026 | 55EB/55F1, 1DB82, 1DE55 | 0 | 1.1 | 0.16 | Cotas relativas del dibujo. La equivalencia con un datum absoluto está pendiente. | Z del modelo = cota relativa + 1,10 m. Correspondencia provisional con 286,10 m; no es cota de obra confirmada. | Sección y contornos del fabricante; incidencias conservadas | 0.4 | 0.4 | La planta general y algunos croquis de apoyo muestran dimensiones transversales distintas. Se usan el contorno de cimentación y los centros de pilares de la implantación general; sección de viga VC1 400 × 400 mm y vuelo a 1050 mm del eje según detalle. / La capa de mortero sobre la losa no tiene una referencia vertical inequívoca; no se duplica una capa independiente en esa losa.
Cimentación y plataforma del módulo LV-CONTAINER · pilar KZ1 02 | Parcela industrial Jinhong | Cimentación industrial | Cimentaciones de equipos y pedestales del fabricante · revisión recibida 04/09/2026 | 0.450754 | 0.450753 | 1.1 | 2.08 | 0.176 | process_plant | Zona de separación de aire | {"name":"Hormigón armado · clase pendiente de confirmar","status":"Clase no confirmada en la hoja de equipo","source":"Geometría de cimentación del fabricante; no se extrapola HA-30 de la nota de pedestales."} | {"documented":[{"label":"Extensión local X","value":0.4,"unit":"m","source":"55EB/55F1, 1DB82, 1DE55","status":"derivada del contorno CAD"},{"label":"Extensión local Y","value":0.4,"unit":"m","source":"55EB/55F1, 1DB82, 1DE55","status":"derivada del contorno CAD"},{"label":"Cota inferior relativa adoptada","value":0,"unit":"m","source":"13–13","status":"interpretación con conflicto conservado"},{"label":"Cota superior relativa adoptada","value":1.1,"unit":"m","source":"13–13","status":"documentada / separación por material"}],"geometry":[{"label":"Extensión de la malla en X","value":0.45075400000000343,"unit":"m","source":"Geometría releída del IFC; datum absoluto de proceso provisional","status":"derivado"},{"label":"Extensión de la malla en Y","value":0.45075300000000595,"unit":"m","source":"Geometría releída del IFC; datum absoluto de proceso provisional","status":"derivado"},{"label":"Extensión de la malla en Z","value":1.1,"unit":"m","source":"Geometría releída del IFC; datum absoluto de proceso provisional","status":"derivado"},{"label":"Cota inferior de visualización","value":286.1,"unit":"m","source":"Geometría releída del IFC; datum absoluto de proceso provisional","status":"derivado"},{"label":"Cota superior de visualización","value":287.2,"unit":"m","source":"Geometría releída del IFC; datum absoluto de proceso provisional","status":"derivado"}]} | {"documentId":"LHD2609-JG00100-20260904","title":"Cimentaciones de equipos y pedestales del fabricante · revisión recibida 04/09/2026","date":"2026-09-04","sheet":"13–13","fileName":"LHD2609-JG00100_20260904.dwg","revisionCaveat":"Fecha de revisión tomada del nombre recibido; cajetines internos mantienen 02/07/2026 y algunos textos de plantilla.","sourceFileSha256":"b42eb027b7bc0b14c38d1d13514f4899b58a732aa8d0ba2ccf10fa2fc3192890"} | provisional | ["La planta general y algunos croquis de apoyo muestran dimensiones transversales distintas. Se usan el contorno de cimentación y los centros de pilares de la implantación general; sección de viga VC1 400 × 400 mm y vuelo a 1050 mm del eje según detalle.","La capa de mortero sobre la losa no tiene una referencia vertical inequívoca; no se duplica una capa independiente en esa losa."] | {"Cota inferior relativa (m)":0,"Cota superior relativa (m)":1.1,"Cero absoluto de visualización (m)":286.1,"Estado del cero absoluto":"Provisional","Criterio":"Las cotas relativas proceden del dibujo; la equivalencia absoluta no está confirmada."} | {"boundingBoxM":{"min":[42.595043,74.933437,1.1],"max":[43.045797,75.38419,2.2]},"extentsM":[0.450754,0.450753,1.1],"meshSurfaceM2":2.079999,"meshVolumeM3":0.176,"closedSolid":true,"basis":"Magnitudes de las mallas representadas, no cantidades certificadas de obra, compra o fabricación. Las partes pueden compartir superficies; no se suman como un despiece de materiales."} | {"profileId":"concrete_reinforced","name":"Hormigón armado · gris natural","materialName":"Hormigón armado · clase pendiente de confirmar","physicalMaterialStatus":"Clase no confirmada en la hoja de equipo","physicalMaterialSource":"Geometría de cimentación del fabricante; no se extrapola HA-30 de la nota de pedestales.","appearanceStatus":"criterio_visual","appearanceBasis":"Interpretación visual del material documental; el acabado, tono y parámetros PBR no son una especificación contractual.","note":"La apariencia gráfica no modifica ni confirma la especificación física del material."} | {"elementId":"found_0904_ddf6874c317c25","ifcGuid":"3fKLSybEvJUh8LkxtMzhh9","ifcClass":"IfcFooting","buildingId":"process_plant","buildingName":"Zona de separación de aire","sourceDocumentId":"LHD2609-JG00100-20260904","sourceRepresentationKind":"foundation"} | {"layerId":"foundations","layerName":"Cimentaciones","role":"Cimentación industrial","basis":"Clasificación por función del elemento; no modifica las especificaciones documentales."} | {"profileId":"concrete_reinforced","name":"Hormigón armado · gris natural","status":"criterio_visual","basis":"Interpretación visual del material documental; el acabado, tono y parámetros PBR no son una especificación contractual.","physicalMaterialUnchanged":true} | 0.176 | Hormigón armado · clase pendiente de confirmar | Hormigón armado · gris natural | found_0904_ddf6874c317c25 | Geometría de cimentación del fabricante; no se extrapola HA-30 de la nota de pedestales. | Clase no confirmada en la hoja de equipo | concrete_reinforced | [0.666667,0.662745,0.619608] | 0.96 | Zona de separación de aire; BIM · Cimentaciones | 0.450754 | 0.450753 | 1.1 | 286.1 | 287.2 | F-LV-CONTAINER | ["LV-CONTAINER"] | [] | 13–13 | ["55EB/55F1","1DB82","1DE55"] | F-LV-CONTAINER/Cimentación y plataforma del módulo LV-CONTAINER · pilar KZ1 02 | foundation | Geometría de fabricante; implantación absoluta provisional | LV-CONTAINER | Cimentaciones de equipos y pedestales del fabricante · revisión recibida 04/09/2026 | 55EB/55F1, 1DB82, 1DE55 | 0 | 1.1 | 0.16 | Cotas relativas del dibujo. La equivalencia con un datum absoluto está pendiente. | Z del modelo = cota relativa + 1,10 m. Correspondencia provisional con 286,10 m; no es cota de obra confirmada. | Sección y contornos del fabricante; incidencias conservadas | 0.4 | 0.4 | La planta general y algunos croquis de apoyo muestran dimensiones transversales distintas. Se usan el contorno de cimentación y los centros de pilares de la implantación general; sección de viga VC1 400 × 400 mm y vuelo a 1050 mm del eje según detalle. / La capa de mortero sobre la losa no tiene una referencia vertical inequívoca; no se duplica una capa independiente en esa losa.
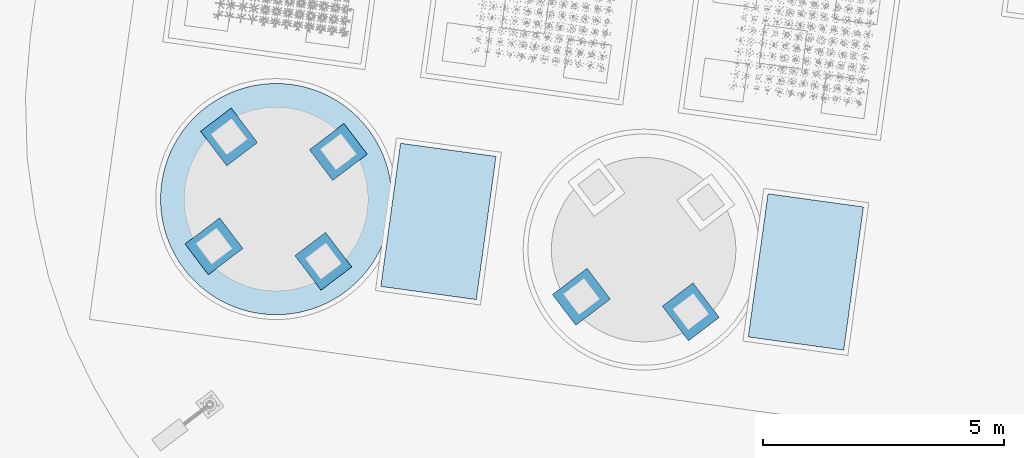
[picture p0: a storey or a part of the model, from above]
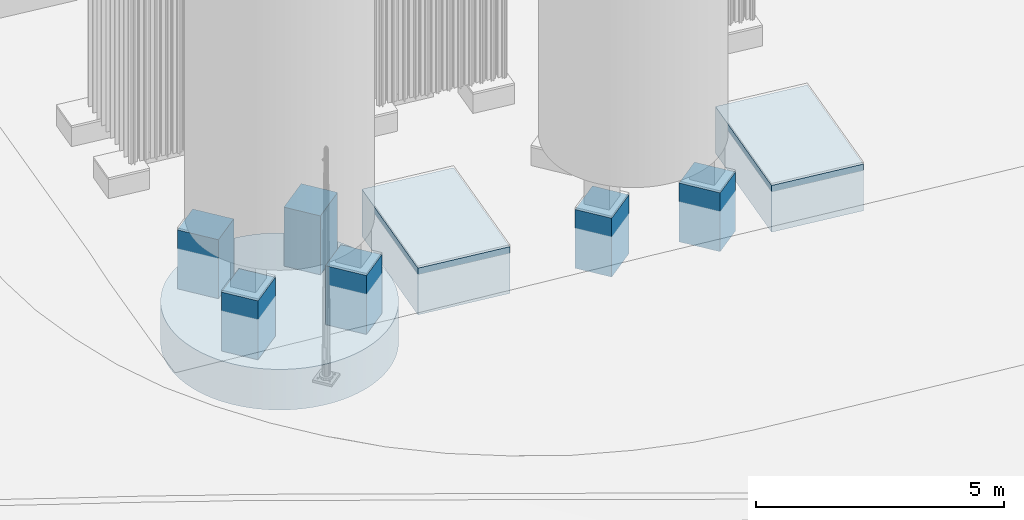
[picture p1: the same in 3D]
Properties of the parts of a building model (IFC4), part 74 of 134

# IfcFooting (214)
Name | In | Description = category = Categoria = Funcion | Document | ExtensionX (m) | ExtensionY (m) | ExtensionZ (m) | SuperficieDeLaMalla (m2) | VolumenGeometrico (m3) | buildingId | buildingName | material | dimensions | JH_InformacionBIM, source = DocumentoFuente | JH_InformacionBIM, status = EstadoDeInformacion | issues = IncidenciasPendientes | positioning = PosicionYEstado | geometryMetrics | materialAppearance | visualizationIdentity | classification | appearance | Volumen geométrico (m³) | JH_Trazabilidad, Material = name | Acabado de visualización = Acabado | Identificador | JH_EvidenciaDeMaterial, source | JH_EvidenciaDeMaterial, status | Perfil | ColorRGB | Rugosidad | Group | Extensión de la malla en X (m) | Extensión de la malla en Y (m) | Extensión de la malla en Z (m) = Espesor o altura real de sección (m) | Cota inferior de visualización (m) | Cota superior de visualización (m) | assemblyId = Conjunto de cimentación | equipmentIds | supportPositionIds | sectionRef = Sección de referencia | sourceCadHandles | stableElementKey | representationKind | geometryStatus | Equipos asociados | Documento de origen | Identificadores CAD de referencia | Cota inferior relativa (m) = Cota inferior relativa adoptada (m) | Cota superior relativa (m) = Cota superior relativa adoptada (m) | Área de planta (m²) | Referencia vertical | Implantación para visualización | Estado de la geometría | Extensión local X (m) | Extensión local Y (m) | Incidencias de origen
Cimentación y plataforma del módulo LV-CONTAINER · pilar KZ1 03 | Parcela industrial Jinhong | Cimentación industrial | Cimentaciones de equipos y pedestales del fabricante · revisión recibida 04/09/2026 | 0.450754 | 0.450754 | 1.1 | 2.08 | 0.176 | process_plant | Zona de separación de aire | {"name":"Hormigón armado · clase pendiente de confirmar","status":"Clase no confirmada en la hoja de equipo","source":"Geometría de cimentación del fabricante; no se extrapola HA-30 de la nota de pedestales."} | {"documented":[{"label":"Extensión local X","value":0.4,"unit":"m","source":"55EB/55F1, 1DB82, 1DE55","status":"derivada del contorno CAD"},{"label":"Extensión local Y","value":0.4,"unit":"m","source":"55EB/55F1, 1DB82, 1DE55","status":"derivada del contorno CAD"},{"label":"Cota inferior relativa adoptada","value":0,"unit":"m","source":"13–13","status":"interpretación con conflicto conservado"},{"label":"Cota superior relativa adoptada","value":1.1,"unit":"m","source":"13–13","status":"documentada / separación por material"}],"geometry":[{"label":"Extensión de la malla en X","value":0.45075400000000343,"unit":"m","source":"Geometría releída del IFC; datum absoluto de proceso provisional","status":"derivado"},{"label":"Extensión de la malla en Y","value":0.4507539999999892,"unit":"m","source":"Geometría releída del IFC; datum absoluto de proceso provisional","status":"derivado"},{"label":"Extensión de la malla en Z","value":1.1,"unit":"m","source":"Geometría releída del IFC; datum absoluto de proceso provisional","status":"derivado"},{"label":"Cota inferior de visualización","value":286.1,"unit":"m","source":"Geometría releída del IFC; datum absoluto de proceso provisional","status":"derivado"},{"label":"Cota superior de visualización","value":287.2,"unit":"m","source":"Geometría releída del IFC; datum absoluto de proceso provisional","status":"derivado"}]} | {"documentId":"LHD2609-JG00100-20260904","title":"Cimentaciones de equipos y pedestales del fabricante · revisión recibida 04/09/2026","date":"2026-09-04","sheet":"13–13","fileName":"LHD2609-JG00100_20260904.dwg","revisionCaveat":"Fecha de revisión tomada del nombre recibido; cajetines internos mantienen 02/07/2026 y algunos textos de plantilla.","sourceFileSha256":"b42eb027b7bc0b14c38d1d13514f4899b58a732aa8d0ba2ccf10fa2fc3192890"} | provisional | ["La planta general y algunos croquis de apoyo muestran dimensiones transversales distintas. Se usan el contorno de cimentación y los centros de pilares de la implantación general; sección de viga VC1 400 × 400 mm y vuelo a 1050 mm del eje según detalle.","La capa de mortero sobre la losa no tiene una referencia vertical inequívoca; no se duplica una capa independiente en esa losa."] | {"Cota inferior relativa (m)":0,"Cota superior relativa (m)":1.1,"Cero absoluto de visualización (m)":286.1,"Estado del cero absoluto":"Provisional","Criterio":"Las cotas relativas proceden del dibujo; la equivalencia absoluta no está confirmada."} | {"boundingBoxM":{"min":[42.884476,77.038633,1.1],"max":[43.33523,77.489387,2.2]},"extentsM":[0.450754,0.450754,1.1],"meshSurfaceM2":2.08,"meshVolumeM3":0.176,"closedSolid":true,"basis":"Magnitudes de las mallas representadas, no cantidades certificadas de obra, compra o fabricación. Las partes pueden compartir superficies; no se suman como un despiece de materiales."} | {"profileId":"concrete_reinforced","name":"Hormigón armado · gris natural","materialName":"Hormigón armado · clase pendiente de confirmar","physicalMaterialStatus":"Clase no confirmada en la hoja de equipo","physicalMaterialSource":"Geometría de cimentación del fabricante; no se extrapola HA-30 de la nota de pedestales.","appearanceStatus":"criterio_visual","appearanceBasis":"Interpretación visual del material documental; el acabado, tono y parámetros PBR no son una especificación contractual.","note":"La apariencia gráfica no modifica ni confirma la especificación física del material."} | {"elementId":"found_0904_54183cb465992b","ifcGuid":"18p_OVN85QofL8Siyt1Yvs","ifcClass":"IfcFooting","buildingId":"process_plant","buildingName":"Zona de separación de aire","sourceDocumentId":"LHD2609-JG00100-20260904","sourceRepresentationKind":"foundation"} | {"layerId":"foundations","layerName":"Cimentaciones","role":"Cimentación industrial","basis":"Clasificación por función del elemento; no modifica las especificaciones documentales."} | {"profileId":"concrete_reinforced","name":"Hormigón armado · gris natural","status":"criterio_visual","basis":"Interpretación visual del material documental; el acabado, tono y parámetros PBR no son una especificación contractual.","physicalMaterialUnchanged":true} | 0.176 | Hormigón armado · clase pendiente de confirmar | Hormigón armado · gris natural | found_0904_54183cb465992b | Geometría de cimentación del fabricante; no se extrapola HA-30 de la nota de pedestales. | Clase no confirmada en la hoja de equipo | concrete_reinforced | [0.666667,0.662745,0.619608] | 0.96 | Zona de separación de aire; BIM · Cimentaciones | 0.450754 | 0.450754 | 1.1 | 286.1 | 287.2 | F-LV-CONTAINER | ["LV-CONTAINER"] | [] | 13–13 | ["55EB/55F1","1DB82","1DE55"] | F-LV-CONTAINER/Cimentación y plataforma del módulo LV-CONTAINER · pilar KZ1 03 | foundation | Geometría de fabricante; implantación absoluta provisional | LV-CONTAINER | Cimentaciones de equipos y pedestales del fabricante · revisión recibida 04/09/2026 | 55EB/55F1, 1DB82, 1DE55 | 0 | 1.1 | 0.16 | Cotas relativas del dibujo. La equivalencia con un datum absoluto está pendiente. | Z del modelo = cota relativa + 1,10 m. Correspondencia provisional con 286,10 m; no es cota de obra confirmada. | Sección y contornos del fabricante; incidencias conservadas | 0.4 | 0.4 | La planta general y algunos croquis de apoyo muestran dimensiones transversales distintas. Se usan el contorno de cimentación y los centros de pilares de la implantación general; sección de viga VC1 400 × 400 mm y vuelo a 1050 mm del eje según detalle. / La capa de mortero sobre la losa no tiene una referencia vertical inequívoca; no se duplica una capa independiente en esa losa.
Cimentación y plataforma del módulo LV-CONTAINER · pilar KZ1 04 | Parcela industrial Jinhong | Cimentación industrial | Cimentaciones de equipos y pedestales del fabricante · revisión recibida 04/09/2026 | 0.450753 | 0.450754 | 1.1 | 2.08 | 0.176 | process_plant | Zona de separación de aire | {"name":"Hormigón armado · clase pendiente de confirmar","status":"Clase no confirmada en la hoja de equipo","source":"Geometría de cimentación del fabricante; no se extrapola HA-30 de la nota de pedestales."} | {"documented":[{"label":"Extensión local X","value":0.4,"unit":"m","source":"55EB/55F1, 1DB82, 1DE55","status":"derivada del contorno CAD"},{"label":"Extensión local Y","value":0.4,"unit":"m","source":"55EB/55F1, 1DB82, 1DE55","status":"derivada del contorno CAD"},{"label":"Cota inferior relativa adoptada","value":0,"unit":"m","source":"13–13","status":"interpretación con conflicto conservado"},{"label":"Cota superior relativa adoptada","value":1.1,"unit":"m","source":"13–13","status":"documentada / separación por material"}],"geometry":[{"label":"Extensión de la malla en X","value":0.45075299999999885,"unit":"m","source":"Geometría releída del IFC; datum absoluto de proceso provisional","status":"derivado"},{"label":"Extensión de la malla en Y","value":0.45075400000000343,"unit":"m","source":"Geometría releída del IFC; datum absoluto de proceso provisional","status":"derivado"},{"label":"Extensión de la malla en Z","value":1.1,"unit":"m","source":"Geometría releída del IFC; datum absoluto de proceso provisional","status":"derivado"},{"label":"Cota inferior de visualización","value":286.1,"unit":"m","source":"Geometría releída del IFC; datum absoluto de proceso provisional","status":"derivado"},{"label":"Cota superior de visualización","value":287.2,"unit":"m","source":"Geometría releída del IFC; datum absoluto de proceso provisional","status":"derivado"}]} | {"documentId":"LHD2609-JG00100-20260904","title":"Cimentaciones de equipos y pedestales del fabricante · revisión recibida 04/09/2026","date":"2026-09-04","sheet":"13–13","fileName":"LHD2609-JG00100_20260904.dwg","revisionCaveat":"Fecha de revisión tomada del nombre recibido; cajetines internos mantienen 02/07/2026 y algunos textos de plantilla.","sourceFileSha256":"b42eb027b7bc0b14c38d1d13514f4899b58a732aa8d0ba2ccf10fa2fc3192890"} | provisional | ["La planta general y algunos croquis de apoyo muestran dimensiones transversales distintas. Se usan el contorno de cimentación y los centros de pilares de la implantación general; sección de viga VC1 400 × 400 mm y vuelo a 1050 mm del eje según detalle.","La capa de mortero sobre la losa no tiene una referencia vertical inequívoca; no se duplica una capa independiente en esa losa."] | {"Cota inferior relativa (m)":0,"Cota superior relativa (m)":1.1,"Cero absoluto de visualización (m)":286.1,"Estado del cero absoluto":"Provisional","Criterio":"Las cotas relativas proceden del dibujo; la equivalencia absoluta no está confirmada."} | {"boundingBoxM":{"min":[43.17391,79.14383,1.1],"max":[43.624663,79.594584,2.2]},"extentsM":[0.450753,0.450754,1.1],"meshSurfaceM2":2.079998,"meshVolumeM3":0.176,"closedSolid":true,"basis":"Magnitudes de las mallas representadas, no cantidades certificadas de obra, compra o fabricación. Las partes pueden compartir superficies; no se suman como un despiece de materiales."} | {"profileId":"concrete_reinforced","name":"Hormigón armado · gris natural","materialName":"Hormigón armado · clase pendiente de confirmar","physicalMaterialStatus":"Clase no confirmada en la hoja de equipo","physicalMaterialSource":"Geometría de cimentación del fabricante; no se extrapola HA-30 de la nota de pedestales.","appearanceStatus":"criterio_visual","appearanceBasis":"Interpretación visual del material documental; el acabado, tono y parámetros PBR no son una especificación contractual.","note":"La apariencia gráfica no modifica ni confirma la especificación física del material."} | {"elementId":"found_0904_703548d0d1268f","ifcGuid":"2T7GrnNkvRzR3edURFrT3a","ifcClass":"IfcFooting","buildingId":"process_plant","buildingName":"Zona de separación de aire","sourceDocumentId":"LHD2609-JG00100-20260904","sourceRepresentationKind":"foundation"} | {"layerId":"foundations","layerName":"Cimentaciones","role":"Cimentación industrial","basis":"Clasificación por función del elemento; no modifica las especificaciones documentales."} | {"profileId":"concrete_reinforced","name":"Hormigón armado · gris natural","status":"criterio_visual","basis":"Interpretación visual del material documental; el acabado, tono y parámetros PBR no son una especificación contractual.","physicalMaterialUnchanged":true} | 0.176 | Hormigón armado · clase pendiente de confirmar | Hormigón armado · gris natural | found_0904_703548d0d1268f | Geometría de cimentación del fabricante; no se extrapola HA-30 de la nota de pedestales. | Clase no confirmada en la hoja de equipo | concrete_reinforced | [0.666667,0.662745,0.619608] | 0.96 | Zona de separación de aire; BIM · Cimentaciones | 0.450753 | 0.450754 | 1.1 | 286.1 | 287.2 | F-LV-CONTAINER | ["LV-CONTAINER"] | [] | 13–13 | ["55EB/55F1","1DB82","1DE55"] | F-LV-CONTAINER/Cimentación y plataforma del módulo LV-CONTAINER · pilar KZ1 04 | foundation | Geometría de fabricante; implantación absoluta provisional | LV-CONTAINER | Cimentaciones de equipos y pedestales del fabricante · revisión recibida 04/09/2026 | 55EB/55F1, 1DB82, 1DE55 | 0 | 1.1 | 0.16 | Cotas relativas del dibujo. La equivalencia con un datum absoluto está pendiente. | Z del modelo = cota relativa + 1,10 m. Correspondencia provisional con 286,10 m; no es cota de obra confirmada. | Sección y contornos del fabricante; incidencias conservadas | 0.4 | 0.4 | La planta general y algunos croquis de apoyo muestran dimensiones transversales distintas. Se usan el contorno de cimentación y los centros de pilares de la implantación general; sección de viga VC1 400 × 400 mm y vuelo a 1050 mm del eje según detalle. / La capa de mortero sobre la losa no tiene una referencia vertical inequívoca; no se duplica una capa independiente en esa losa.
Cimentación y plataforma del módulo LV-CONTAINER · pilar KZ1 05 | Parcela industrial Jinhong | Cimentación industrial | Cimentaciones de equipos y pedestales del fabricante · revisión recibida 04/09/2026 | 0.450754 | 0.450754 | 1.1 | 2.08 | 0.176 | process_plant | Zona de separación de aire | {"name":"Hormigón armado · clase pendiente de confirmar","status":"Clase no confirmada en la hoja de equipo","source":"Geometría de cimentación del fabricante; no se extrapola HA-30 de la nota de pedestales."} | {"documented":[{"label":"Extensión local X","value":0.4,"unit":"m","source":"55EB/55F1, 1DB82, 1DE55","status":"derivada del contorno CAD"},{"label":"Extensión local Y","value":0.4,"unit":"m","source":"55EB/55F1, 1DB82, 1DE55","status":"derivada del contorno CAD"},{"label":"Cota inferior relativa adoptada","value":0,"unit":"m","source":"13–13","status":"interpretación con conflicto conservado"},{"label":"Cota superior relativa adoptada","value":1.1,"unit":"m","source":"13–13","status":"documentada / separación por material"}],"geometry":[{"label":"Extensión de la malla en X","value":0.4507539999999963,"unit":"m","source":"Geometría releída del IFC; datum absoluto de proceso provisional","status":"derivado"},{"label":"Extensión de la malla en Y","value":0.45075400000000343,"unit":"m","source":"Geometría releída del IFC; datum absoluto de proceso provisional","status":"derivado"},{"label":"Extensión de la malla en Z","value":1.1,"unit":"m","source":"Geometría releída del IFC; datum absoluto de proceso provisional","status":"derivado"},{"label":"Cota inferior de visualización","value":286.1,"unit":"m","source":"Geometría releída del IFC; datum absoluto de proceso provisional","status":"derivado"},{"label":"Cota superior de visualización","value":287.2,"unit":"m","source":"Geometría releída del IFC; datum absoluto de proceso provisional","status":"derivado"}]} | {"documentId":"LHD2609-JG00100-20260904","title":"Cimentaciones de equipos y pedestales del fabricante · revisión recibida 04/09/2026","date":"2026-09-04","sheet":"13–13","fileName":"LHD2609-JG00100_20260904.dwg","revisionCaveat":"Fecha de revisión tomada del nombre recibido; cajetines internos mantienen 02/07/2026 y algunos textos de plantilla.","sourceFileSha256":"b42eb027b7bc0b14c38d1d13514f4899b58a732aa8d0ba2ccf10fa2fc3192890"} | provisional | ["La planta general y algunos croquis de apoyo muestran dimensiones transversales distintas. Se usan el contorno de cimentación y los centros de pilares de la implantación general; sección de viga VC1 400 × 400 mm y vuelo a 1050 mm del eje según detalle.","La capa de mortero sobre la losa no tiene una referencia vertical inequívoca; no se duplica una capa independiente en esa losa."] | {"Cota inferior relativa (m)":0,"Cota superior relativa (m)":1.1,"Cero absoluto de visualización (m)":286.1,"Estado del cero absoluto":"Provisional","Criterio":"Las cotas relativas proceden del dibujo; la equivalencia absoluta no está confirmada."} | {"boundingBoxM":{"min":[43.463343,81.249027,1.1],"max":[43.914097,81.699781,2.2]},"extentsM":[0.450754,0.450754,1.1],"meshSurfaceM2":2.080001,"meshVolumeM3":0.176,"closedSolid":true,"basis":"Magnitudes de las mallas representadas, no cantidades certificadas de obra, compra o fabricación. Las partes pueden compartir superficies; no se suman como un despiece de materiales."} | {"profileId":"concrete_reinforced","name":"Hormigón armado · gris natural","materialName":"Hormigón armado · clase pendiente de confirmar","physicalMaterialStatus":"Clase no confirmada en la hoja de equipo","physicalMaterialSource":"Geometría de cimentación del fabricante; no se extrapola HA-30 de la nota de pedestales.","appearanceStatus":"criterio_visual","appearanceBasis":"Interpretación visual del material documental; el acabado, tono y parámetros PBR no son una especificación contractual.","note":"La apariencia gráfica no modifica ni confirma la especificación física del material."} | {"elementId":"found_0904_b3a9a2c40a9ee0","ifcGuid":"2_BNH8Q9bStQnWvIHKtIlX","ifcClass":"IfcFooting","buildingId":"process_plant","buildingName":"Zona de separación de aire","sourceDocumentId":"LHD2609-JG00100-20260904","sourceRepresentationKind":"foundation"} | {"layerId":"foundations","layerName":"Cimentaciones","role":"Cimentación industrial","basis":"Clasificación por función del elemento; no modifica las especificaciones documentales."} | {"profileId":"concrete_reinforced","name":"Hormigón armado · gris natural","status":"criterio_visual","basis":"Interpretación visual del material documental; el acabado, tono y parámetros PBR no son una especificación contractual.","physicalMaterialUnchanged":true} | 0.176 | Hormigón armado · clase pendiente de confirmar | Hormigón armado · gris natural | found_0904_b3a9a2c40a9ee0 | Geometría de cimentación del fabricante; no se extrapola HA-30 de la nota de pedestales. | Clase no confirmada en la hoja de equipo | concrete_reinforced | [0.666667,0.662745,0.619608] | 0.96 | Zona de separación de aire; BIM · Cimentaciones | 0.450754 | 0.450754 | 1.1 | 286.1 | 287.2 | F-LV-CONTAINER | ["LV-CONTAINER"] | [] | 13–13 | ["55EB/55F1","1DB82","1DE55"] | F-LV-CONTAINER/Cimentación y plataforma del módulo LV-CONTAINER · pilar KZ1 05 | foundation | Geometría de fabricante; implantación absoluta provisional | LV-CONTAINER | Cimentaciones de equipos y pedestales del fabricante · revisión recibida 04/09/2026 | 55EB/55F1, 1DB82, 1DE55 | 0 | 1.1 | 0.16 | Cotas relativas del dibujo. La equivalencia con un datum absoluto está pendiente. | Z del modelo = cota relativa + 1,10 m. Correspondencia provisional con 286,10 m; no es cota de obra confirmada. | Sección y contornos del fabricante; incidencias conservadas | 0.4 | 0.4 | La planta general y algunos croquis de apoyo muestran dimensiones transversales distintas. Se usan el contorno de cimentación y los centros de pilares de la implantación general; sección de viga VC1 400 × 400 mm y vuelo a 1050 mm del eje según detalle. / La capa de mortero sobre la losa no tiene una referencia vertical inequívoca; no se duplica una capa independiente en esa losa.
Cimentación y plataforma del módulo LV-CONTAINER · pilar KZ1 06 | Parcela industrial Jinhong | Cimentación industrial | Cimentaciones de equipos y pedestales del fabricante · revisión recibida 04/09/2026 | 0.450754 | 0.450754 | 1.1 | 2.08 | 0.176 | process_plant | Zona de separación de aire | {"name":"Hormigón armado · clase pendiente de confirmar","status":"Clase no confirmada en la hoja de equipo","source":"Geometría de cimentación del fabricante; no se extrapola HA-30 de la nota de pedestales."} | {"documented":[{"label":"Extensión local X","value":0.4,"unit":"m","source":"55EB/55F1, 1DB82, 1DE55","status":"derivada del contorno CAD"},{"label":"Extensión local Y","value":0.4,"unit":"m","source":"55EB/55F1, 1DB82, 1DE55","status":"derivada del contorno CAD"},{"label":"Cota inferior relativa adoptada","value":0,"unit":"m","source":"13–13","status":"interpretación con conflicto conservado"},{"label":"Cota superior relativa adoptada","value":1.1,"unit":"m","source":"13–13","status":"documentada / separación por material"}],"geometry":[{"label":"Extensión de la malla en X","value":0.4507539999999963,"unit":"m","source":"Geometría releída del IFC; datum absoluto de proceso provisional","status":"derivado"},{"label":"Extensión de la malla en Y","value":0.45075400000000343,"unit":"m","source":"Geometría releída del IFC; datum absoluto de proceso provisional","status":"derivado"},{"label":"Extensión de la malla en Z","value":1.1,"unit":"m","source":"Geometría releída del IFC; datum absoluto de proceso provisional","status":"derivado"},{"label":"Cota inferior de visualización","value":286.1,"unit":"m","source":"Geometría releída del IFC; datum absoluto de proceso provisional","status":"derivado"},{"label":"Cota superior de visualización","value":287.2,"unit":"m","source":"Geometría releída del IFC; datum absoluto de proceso provisional","status":"derivado"}]} | {"documentId":"LHD2609-JG00100-20260904","title":"Cimentaciones de equipos y pedestales del fabricante · revisión recibida 04/09/2026","date":"2026-09-04","sheet":"13–13","fileName":"LHD2609-JG00100_20260904.dwg","revisionCaveat":"Fecha de revisión tomada del nombre recibido; cajetines internos mantienen 02/07/2026 y algunos textos de plantilla.","sourceFileSha256":"b42eb027b7bc0b14c38d1d13514f4899b58a732aa8d0ba2ccf10fa2fc3192890"} | provisional | ["La planta general y algunos croquis de apoyo muestran dimensiones transversales distintas. Se usan el contorno de cimentación y los centros de pilares de la implantación general; sección de viga VC1 400 × 400 mm y vuelo a 1050 mm del eje según detalle.","La capa de mortero sobre la losa no tiene una referencia vertical inequívoca; no se duplica una capa independiente en esa losa."] | {"Cota inferior relativa (m)":0,"Cota superior relativa (m)":1.1,"Cero absoluto de visualización (m)":286.1,"Estado del cero absoluto":"Provisional","Criterio":"Las cotas relativas proceden del dibujo; la equivalencia absoluta no está confirmada."} | {"boundingBoxM":{"min":[39.383101,73.230041,1.1],"max":[39.833855,73.680795,2.2]},"extentsM":[0.450754,0.450754,1.1],"meshSurfaceM2":2.08,"meshVolumeM3":0.176,"closedSolid":true,"basis":"Magnitudes de las mallas representadas, no cantidades certificadas de obra, compra o fabricación. Las partes pueden compartir superficies; no se suman como un despiece de materiales."} | {"profileId":"concrete_reinforced","name":"Hormigón armado · gris natural","materialName":"Hormigón armado · clase pendiente de confirmar","physicalMaterialStatus":"Clase no confirmada en la hoja de equipo","physicalMaterialSource":"Geometría de cimentación del fabricante; no se extrapola HA-30 de la nota de pedestales.","appearanceStatus":"criterio_visual","appearanceBasis":"Interpretación visual del material documental; el acabado, tono y parámetros PBR no son una especificación contractual.","note":"La apariencia gráfica no modifica ni confirma la especificación física del material."} | {"elementId":"found_0904_7f9093c00ae6c1","ifcGuid":"09nHpnGs1NsQ1m$ZyX01ey","ifcClass":"IfcFooting","buildingId":"process_plant","buildingName":"Zona de separación de aire","sourceDocumentId":"LHD2609-JG00100-20260904","sourceRepresentationKind":"foundation"} | {"layerId":"foundations","layerName":"Cimentaciones","role":"Cimentación industrial","basis":"Clasificación por función del elemento; no modifica las especificaciones documentales."} | {"profileId":"concrete_reinforced","name":"Hormigón armado · gris natural","status":"criterio_visual","basis":"Interpretación visual del material documental; el acabado, tono y parámetros PBR no son una especificación contractual.","physicalMaterialUnchanged":true} | 0.176 | Hormigón armado · clase pendiente de confirmar | Hormigón armado · gris natural | found_0904_7f9093c00ae6c1 | Geometría de cimentación del fabricante; no se extrapola HA-30 de la nota de pedestales. | Clase no confirmada en la hoja de equipo | concrete_reinforced | [0.666667,0.662745,0.619608] | 0.96 | Zona de separación de aire; BIM · Cimentaciones | 0.450754 | 0.450754 | 1.1 | 286.1 | 287.2 | F-LV-CONTAINER | ["LV-CONTAINER"] | [] | 13–13 | ["55EB/55F1","1DB82","1DE55"] | F-LV-CONTAINER/Cimentación y plataforma del módulo LV-CONTAINER · pilar KZ1 06 | foundation | Geometría de fabricante; implantación absoluta provisional | LV-CONTAINER | Cimentaciones de equipos y pedestales del fabricante · revisión recibida 04/09/2026 | 55EB/55F1, 1DB82, 1DE55 | 0 | 1.1 | 0.16 | Cotas relativas del dibujo. La equivalencia con un datum absoluto está pendiente. | Z del modelo = cota relativa + 1,10 m. Correspondencia provisional con 286,10 m; no es cota de obra confirmada. | Sección y contornos del fabricante; incidencias conservadas | 0.4 | 0.4 | La planta general y algunos croquis de apoyo muestran dimensiones transversales distintas. Se usan el contorno de cimentación y los centros de pilares de la implantación general; sección de viga VC1 400 × 400 mm y vuelo a 1050 mm del eje según detalle. / La capa de mortero sobre la losa no tiene una referencia vertical inequívoca; no se duplica una capa independiente en esa losa.
Cimentación y plataforma del módulo LV-CONTAINER · pilar KZ1 07 | Parcela industrial Jinhong | Cimentación industrial | Cimentaciones de equipos y pedestales del fabricante · revisión recibida 04/09/2026 | 0.450754 | 0.450754 | 1.1 | 2.08 | 0.176 | process_plant | Zona de separación de aire | {"name":"Hormigón armado · clase pendiente de confirmar","status":"Clase no confirmada en la hoja de equipo","source":"Geometría de cimentación del fabricante; no se extrapola HA-30 de la nota de pedestales."} | {"documented":[{"label":"Extensión local X","value":0.4,"unit":"m","source":"55EB/55F1, 1DB82, 1DE55","status":"derivada del contorno CAD"},{"label":"Extensión local Y","value":0.4,"unit":"m","source":"55EB/55F1, 1DB82, 1DE55","status":"derivada del contorno CAD"},{"label":"Cota inferior relativa adoptada","value":0,"unit":"m","source":"13–13","status":"interpretación con conflicto conservado"},{"label":"Cota superior relativa adoptada","value":1.1,"unit":"m","source":"13–13","status":"documentada / separación por material"}],"geometry":[{"label":"Extensión de la malla en X","value":0.45075400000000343,"unit":"m","source":"Geometría releída del IFC; datum absoluto de proceso provisional","status":"derivado"},{"label":"Extensión de la malla en Y","value":0.4507539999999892,"unit":"m","source":"Geometría releída del IFC; datum absoluto de proceso provisional","status":"derivado"},{"label":"Extensión de la malla en Z","value":1.1,"unit":"m","source":"Geometría releída del IFC; datum absoluto de proceso provisional","status":"derivado"},{"label":"Cota inferior de visualización","value":286.1,"unit":"m","source":"Geometría releída del IFC; datum absoluto de proceso provisional","status":"derivado"},{"label":"Cota superior de visualización","value":287.2,"unit":"m","source":"Geometría releída del IFC; datum absoluto de proceso provisional","status":"derivado"}]} | {"documentId":"LHD2609-JG00100-20260904","title":"Cimentaciones de equipos y pedestales del fabricante · revisión recibida 04/09/2026","date":"2026-09-04","sheet":"13–13","fileName":"LHD2609-JG00100_20260904.dwg","revisionCaveat":"Fecha de revisión tomada del nombre recibido; cajetines internos mantienen 02/07/2026 y algunos textos de plantilla.","sourceFileSha256":"b42eb027b7bc0b14c38d1d13514f4899b58a732aa8d0ba2ccf10fa2fc3192890"} | provisional | ["La planta general y algunos croquis de apoyo muestran dimensiones transversales distintas. Se usan el contorno de cimentación y los centros de pilares de la implantación general; sección de viga VC1 400 × 400 mm y vuelo a 1050 mm del eje según detalle.","La capa de mortero sobre la losa no tiene una referencia vertical inequívoca; no se duplica una capa independiente en esa losa."] | {"Cota inferior relativa (m)":0,"Cota superior relativa (m)":1.1,"Cero absoluto de visualización (m)":286.1,"Estado del cero absoluto":"Provisional","Criterio":"Las cotas relativas proceden del dibujo; la equivalencia absoluta no está confirmada."} | {"boundingBoxM":{"min":[39.672534,75.335238,1.1],"max":[40.123288,75.785992,2.2]},"extentsM":[0.450754,0.450754,1.1],"meshSurfaceM2":2.08,"meshVolumeM3":0.176,"closedSolid":true,"basis":"Magnitudes de las mallas representadas, no cantidades certificadas de obra, compra o fabricación. Las partes pueden compartir superficies; no se suman como un despiece de materiales."} | {"profileId":"concrete_reinforced","name":"Hormigón armado · gris natural","materialName":"Hormigón armado · clase pendiente de confirmar","physicalMaterialStatus":"Clase no confirmada en la hoja de equipo","physicalMaterialSource":"Geometría de cimentación del fabricante; no se extrapola HA-30 de la nota de pedestales.","appearanceStatus":"criterio_visual","appearanceBasis":"Interpretación visual del material documental; el acabado, tono y parámetros PBR no son una especificación contractual.","note":"La apariencia gráfica no modifica ni confirma la especificación física del material."} | {"elementId":"found_0904_ac15fe863abb4f","ifcGuid":"3T4bE4d9zMFAV9AZbe0UV5","ifcClass":"IfcFooting","buildingId":"process_plant","buildingName":"Zona de separación de aire","sourceDocumentId":"LHD2609-JG00100-20260904","sourceRepresentationKind":"foundation"} | {"layerId":"foundations","layerName":"Cimentaciones","role":"Cimentación industrial","basis":"Clasificación por función del elemento; no modifica las especificaciones documentales."} | {"profileId":"concrete_reinforced","name":"Hormigón armado · gris natural","status":"criterio_visual","basis":"Interpretación visual del material documental; el acabado, tono y parámetros PBR no son una especificación contractual.","physicalMaterialUnchanged":true} | 0.176 | Hormigón armado · clase pendiente de confirmar | Hormigón armado · gris natural | found_0904_ac15fe863abb4f | Geometría de cimentación del fabricante; no se extrapola HA-30 de la nota de pedestales. | Clase no confirmada en la hoja de equipo | concrete_reinforced | [0.666667,0.662745,0.619608] | 0.96 | Zona de separación de aire; BIM · Cimentaciones | 0.450754 | 0.450754 | 1.1 | 286.1 | 287.2 | F-LV-CONTAINER | ["LV-CONTAINER"] | [] | 13–13 | ["55EB/55F1","1DB82","1DE55"] | F-LV-CONTAINER/Cimentación y plataforma del módulo LV-CONTAINER · pilar KZ1 07 | foundation | Geometría de fabricante; implantación absoluta provisional | LV-CONTAINER | Cimentaciones de equipos y pedestales del fabricante · revisión recibida 04/09/2026 | 55EB/55F1, 1DB82, 1DE55 | 0 | 1.1 | 0.16 | Cotas relativas del dibujo. La equivalencia con un datum absoluto está pendiente. | Z del modelo = cota relativa + 1,10 m. Correspondencia provisional con 286,10 m; no es cota de obra confirmada. | Sección y contornos del fabricante; incidencias conservadas | 0.4 | 0.4 | La planta general y algunos croquis de apoyo muestran dimensiones transversales distintas. Se usan el contorno de cimentación y los centros de pilares de la implantación general; sección de viga VC1 400 × 400 mm y vuelo a 1050 mm del eje según detalle. / La capa de mortero sobre la losa no tiene una referencia vertical inequívoca; no se duplica una capa independiente en esa losa.
Cimentación y plataforma del módulo LV-CONTAINER · pilar KZ1 08 | Parcela industrial Jinhong | Cimentación industrial | Cimentaciones de equipos y pedestales del fabricante · revisión recibida 04/09/2026 | 0.450754 | 0.450754 | 1.1 | 2.08 | 0.176 | process_plant | Zona de separación de aire | {"name":"Hormigón armado · clase pendiente de confirmar","status":"Clase no confirmada en la hoja de equipo","source":"Geometría de cimentación del fabricante; no se extrapola HA-30 de la nota de pedestales."} | {"documented":[{"label":"Extensión local X","value":0.4,"unit":"m","source":"55EB/55F1, 1DB82, 1DE55","status":"derivada del contorno CAD"},{"label":"Extensión local Y","value":0.4,"unit":"m","source":"55EB/55F1, 1DB82, 1DE55","status":"derivada del contorno CAD"},{"label":"Cota inferior relativa adoptada","value":0,"unit":"m","source":"13–13","status":"interpretación con conflicto conservado"},{"label":"Cota superior relativa adoptada","value":1.1,"unit":"m","source":"13–13","status":"documentada / separación por material"}],"geometry":[{"label":"Extensión de la malla en X","value":0.45075400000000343,"unit":"m","source":"Geometría releída del IFC; datum absoluto de proceso provisional","status":"derivado"},{"label":"Extensión de la malla en Y","value":0.45075400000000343,"unit":"m","source":"Geometría releída del IFC; datum absoluto de proceso provisional","status":"derivado"},{"label":"Extensión de la malla en Z","value":1.1,"unit":"m","source":"Geometría releída del IFC; datum absoluto de proceso provisional","status":"derivado"},{"label":"Cota inferior de visualización","value":286.1,"unit":"m","source":"Geometría releída del IFC; datum absoluto de proceso provisional","status":"derivado"},{"label":"Cota superior de visualización","value":287.2,"unit":"m","source":"Geometría releída del IFC; datum absoluto de proceso provisional","status":"derivado"}]} | {"documentId":"LHD2609-JG00100-20260904","title":"Cimentaciones de equipos y pedestales del fabricante · revisión recibida 04/09/2026","date":"2026-09-04","sheet":"13–13","fileName":"LHD2609-JG00100_20260904.dwg","revisionCaveat":"Fecha de revisión tomada del nombre recibido; cajetines internos mantienen 02/07/2026 y algunos textos de plantilla.","sourceFileSha256":"b42eb027b7bc0b14c38d1d13514f4899b58a732aa8d0ba2ccf10fa2fc3192890"} | provisional | ["La planta general y algunos croquis de apoyo muestran dimensiones transversales distintas. Se usan el contorno de cimentación y los centros de pilares de la implantación general; sección de viga VC1 400 × 400 mm y vuelo a 1050 mm del eje según detalle.","La capa de mortero sobre la losa no tiene una referencia vertical inequívoca; no se duplica una capa independiente en esa losa."] | {"Cota inferior relativa (m)":0,"Cota superior relativa (m)":1.1,"Cero absoluto de visualización (m)":286.1,"Estado del cero absoluto":"Provisional","Criterio":"Las cotas relativas proceden del dibujo; la equivalencia absoluta no está confirmada."} | {"boundingBoxM":{"min":[39.961968,77.440435,1.1],"max":[40.412722,77.891189,2.2]},"extentsM":[0.450754,0.450754,1.1],"meshSurfaceM2":2.080001,"meshVolumeM3":0.176,"closedSolid":true,"basis":"Magnitudes de las mallas representadas, no cantidades certificadas de obra, compra o fabricación. Las partes pueden compartir superficies; no se suman como un despiece de materiales."} | {"profileId":"concrete_reinforced","name":"Hormigón armado · gris natural","materialName":"Hormigón armado · clase pendiente de confirmar","physicalMaterialStatus":"Clase no confirmada en la hoja de equipo","physicalMaterialSource":"Geometría de cimentación del fabricante; no se extrapola HA-30 de la nota de pedestales.","appearanceStatus":"criterio_visual","appearanceBasis":"Interpretación visual del material documental; el acabado, tono y parámetros PBR no son una especificación contractual.","note":"La apariencia gráfica no modifica ni confirma la especificación física del material."} | {"elementId":"found_0904_2a64ff58200521","ifcGuid":"3S3bSUrTjQahh$smy$PYR0","ifcClass":"IfcFooting","buildingId":"process_plant","buildingName":"Zona de separación de aire","sourceDocumentId":"LHD2609-JG00100-20260904","sourceRepresentationKind":"foundation"} | {"layerId":"foundations","layerName":"Cimentaciones","role":"Cimentación industrial","basis":"Clasificación por función del elemento; no modifica las especificaciones documentales."} | {"profileId":"concrete_reinforced","name":"Hormigón armado · gris natural","status":"criterio_visual","basis":"Interpretación visual del material documental; el acabado, tono y parámetros PBR no son una especificación contractual.","physicalMaterialUnchanged":true} | 0.176 | Hormigón armado · clase pendiente de confirmar | Hormigón armado · gris natural | found_0904_2a64ff58200521 | Geometría de cimentación del fabricante; no se extrapola HA-30 de la nota de pedestales. | Clase no confirmada en la hoja de equipo | concrete_reinforced | [0.666667,0.662745,0.619608] | 0.96 | Zona de separación de aire; BIM · Cimentaciones | 0.450754 | 0.450754 | 1.1 | 286.1 | 287.2 | F-LV-CONTAINER | ["LV-CONTAINER"] | [] | 13–13 | ["55EB/55F1","1DB82","1DE55"] | F-LV-CONTAINER/Cimentación y plataforma del módulo LV-CONTAINER · pilar KZ1 08 | foundation | Geometría de fabricante; implantación absoluta provisional | LV-CONTAINER | Cimentaciones de equipos y pedestales del fabricante · revisión recibida 04/09/2026 | 55EB/55F1, 1DB82, 1DE55 | 0 | 1.1 | 0.16 | Cotas relativas del dibujo. La equivalencia con un datum absoluto está pendiente. | Z del modelo = cota relativa + 1,10 m. Correspondencia provisional con 286,10 m; no es cota de obra confirmada. | Sección y contornos del fabricante; incidencias conservadas | 0.4 | 0.4 | La planta general y algunos croquis de apoyo muestran dimensiones transversales distintas. Se usan el contorno de cimentación y los centros de pilares de la implantación general; sección de viga VC1 400 × 400 mm y vuelo a 1050 mm del eje según detalle. / La capa de mortero sobre la losa no tiene una referencia vertical inequívoca; no se duplica una capa independiente en esa losa.
Cimentación y plataforma del módulo LV-CONTAINER · pilar KZ1 09 | Parcela industrial Jinhong | Cimentación industrial | Cimentaciones de equipos y pedestales del fabricante · revisión recibida 04/09/2026 | 0.450754 | 0.450753 | 1.1 | 2.08 | 0.176 | process_plant | Zona de separación de aire | {"name":"Hormigón armado · clase pendiente de confirmar","status":"Clase no confirmada en la hoja de equipo","source":"Geometría de cimentación del fabricante; no se extrapola HA-30 de la nota de pedestales."} | {"documented":[{"label":"Extensión local X","value":0.4,"unit":"m","source":"55EB/55F1, 1DB82, 1DE55","status":"derivada del contorno CAD"},{"label":"Extensión local Y","value":0.4,"unit":"m","source":"55EB/55F1, 1DB82, 1DE55","status":"derivada del contorno CAD"},{"label":"Cota inferior relativa adoptada","value":0,"unit":"m","source":"13–13","status":"interpretación con conflicto conservado"},{"label":"Cota superior relativa adoptada","value":1.1,"unit":"m","source":"13–13","status":"documentada / separación por material"}],"geometry":[{"label":"Extensión de la malla en X","value":0.4507539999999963,"unit":"m","source":"Geometría releída del IFC; datum absoluto de proceso provisional","status":"derivado"},{"label":"Extensión de la malla en Y","value":0.45075300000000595,"unit":"m","source":"Geometría releída del IFC; datum absoluto de proceso provisional","status":"derivado"},{"label":"Extensión de la malla en Z","value":1.1,"unit":"m","source":"Geometría releída del IFC; datum absoluto de proceso provisional","status":"derivado"},{"label":"Cota inferior de visualización","value":286.1,"unit":"m","source":"Geometría releída del IFC; datum absoluto de proceso provisional","status":"derivado"},{"label":"Cota superior de visualización","value":287.2,"unit":"m","source":"Geometría releída del IFC; datum absoluto de proceso provisional","status":"derivado"}]} | {"documentId":"LHD2609-JG00100-20260904","title":"Cimentaciones de equipos y pedestales del fabricante · revisión recibida 04/09/2026","date":"2026-09-04","sheet":"13–13","fileName":"LHD2609-JG00100_20260904.dwg","revisionCaveat":"Fecha de revisión tomada del nombre recibido; cajetines internos mantienen 02/07/2026 y algunos textos de plantilla.","sourceFileSha256":"b42eb027b7bc0b14c38d1d13514f4899b58a732aa8d0ba2ccf10fa2fc3192890"} | provisional | ["La planta general y algunos croquis de apoyo muestran dimensiones transversales distintas. Se usan el contorno de cimentación y los centros de pilares de la implantación general; sección de viga VC1 400 × 400 mm y vuelo a 1050 mm del eje según detalle.","La capa de mortero sobre la losa no tiene una referencia vertical inequívoca; no se duplica una capa independiente en esa losa."] | {"Cota inferior relativa (m)":0,"Cota superior relativa (m)":1.1,"Cero absoluto de visualización (m)":286.1,"Estado del cero absoluto":"Provisional","Criterio":"Las cotas relativas proceden del dibujo; la equivalencia absoluta no está confirmada."} | {"boundingBoxM":{"min":[40.251401,79.545632,1.1],"max":[40.702155,79.996385,2.2]},"extentsM":[0.450754,0.450753,1.1],"meshSurfaceM2":2.079998,"meshVolumeM3":0.176,"closedSolid":true,"basis":"Magnitudes de las mallas representadas, no cantidades certificadas de obra, compra o fabricación. Las partes pueden compartir superficies; no se suman como un despiece de materiales."} | {"profileId":"concrete_reinforced","name":"Hormigón armado · gris natural","materialName":"Hormigón armado · clase pendiente de confirmar","physicalMaterialStatus":"Clase no confirmada en la hoja de equipo","physicalMaterialSource":"Geometría de cimentación del fabricante; no se extrapola HA-30 de la nota de pedestales.","appearanceStatus":"criterio_visual","appearanceBasis":"Interpretación visual del material documental; el acabado, tono y parámetros PBR no son una especificación contractual.","note":"La apariencia gráfica no modifica ni confirma la especificación física del material."} | {"elementId":"found_0904_cbb8e054dcc1c6","ifcGuid":"3LQte5BH5LgOllZPpwusQi","ifcClass":"IfcFooting","buildingId":"process_plant","buildingName":"Zona de separación de aire","sourceDocumentId":"LHD2609-JG00100-20260904","sourceRepresentationKind":"foundation"} | {"layerId":"foundations","layerName":"Cimentaciones","role":"Cimentación industrial","basis":"Clasificación por función del elemento; no modifica las especificaciones documentales."} | {"profileId":"concrete_reinforced","name":"Hormigón armado · gris natural","status":"criterio_visual","basis":"Interpretación visual del material documental; el acabado, tono y parámetros PBR no son una especificación contractual.","physicalMaterialUnchanged":true} | 0.176 | Hormigón armado · clase pendiente de confirmar | Hormigón armado · gris natural | found_0904_cbb8e054dcc1c6 | Geometría de cimentación del fabricante; no se extrapola HA-30 de la nota de pedestales. | Clase no confirmada en la hoja de equipo | concrete_reinforced | [0.666667,0.662745,0.619608] | 0.96 | Zona de separación de aire; BIM · Cimentaciones | 0.450754 | 0.450753 | 1.1 | 286.1 | 287.2 | F-LV-CONTAINER | ["LV-CONTAINER"] | [] | 13–13 | ["55EB/55F1","1DB82","1DE55"] | F-LV-CONTAINER/Cimentación y plataforma del módulo LV-CONTAINER · pilar KZ1 09 | foundation | Geometría de fabricante; implantación absoluta provisional | LV-CONTAINER | Cimentaciones de equipos y pedestales del fabricante · revisión recibida 04/09/2026 | 55EB/55F1, 1DB82, 1DE55 | 0 | 1.1 | 0.16 | Cotas relativas del dibujo. La equivalencia con un datum absoluto está pendiente. | Z del modelo = cota relativa + 1,10 m. Correspondencia provisional con 286,10 m; no es cota de obra confirmada. | Sección y contornos del fabricante; incidencias conservadas | 0.4 | 0.4 | La planta general y algunos croquis de apoyo muestran dimensiones transversales distintas. Se usan el contorno de cimentación y los centros de pilares de la implantación general; sección de viga VC1 400 × 400 mm y vuelo a 1050 mm del eje según detalle. / La capa de mortero sobre la losa no tiene una referencia vertical inequívoca; no se duplica una capa independiente en esa losa.
Cimentación y plataforma del módulo LV-CONTAINER · pilar KZ1 10 | Parcela industrial Jinhong | Cimentación industrial | Cimentaciones de equipos y pedestales del fabricante · revisión recibida 04/09/2026 | 0.450754 | 0.450754 | 1.1 | 2.08 | 0.176 | process_plant | Zona de separación de aire | {"name":"Hormigón armado · clase pendiente de confirmar","status":"Clase no confirmada en la hoja de equipo","source":"Geometría de cimentación del fabricante; no se extrapola HA-30 de la nota de pedestales."} | {"documented":[{"label":"Extensión local X","value":0.4,"unit":"m","source":"55EB/55F1, 1DB82, 1DE55","status":"derivada del contorno CAD"},{"label":"Extensión local Y","value":0.4,"unit":"m","source":"55EB/55F1, 1DB82, 1DE55","status":"derivada del contorno CAD"},{"label":"Cota inferior relativa adoptada","value":0,"unit":"m","source":"13–13","status":"interpretación con conflicto conservado"},{"label":"Cota superior relativa adoptada","value":1.1,"unit":"m","source":"13–13","status":"documentada / separación por material"}],"geometry":[{"label":"Extensión de la malla en X","value":0.45075400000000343,"unit":"m","source":"Geometría releída del IFC; datum absoluto de proceso provisional","status":"derivado"},{"label":"Extensión de la malla en Y","value":0.4507539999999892,"unit":"m","source":"Geometría releída del IFC; datum absoluto de proceso provisional","status":"derivado"},{"label":"Extensión de la malla en Z","value":1.1,"unit":"m","source":"Geometría releída del IFC; datum absoluto de proceso provisional","status":"derivado"},{"label":"Cota inferior de visualización","value":286.1,"unit":"m","source":"Geometría releída del IFC; datum absoluto de proceso provisional","status":"derivado"},{"label":"Cota superior de visualización","value":287.2,"unit":"m","source":"Geometría releída del IFC; datum absoluto de proceso provisional","status":"derivado"}]} | {"documentId":"LHD2609-JG00100-20260904","title":"Cimentaciones de equipos y pedestales del fabricante · revisión recibida 04/09/2026","date":"2026-09-04","sheet":"13–13","fileName":"LHD2609-JG00100_20260904.dwg","revisionCaveat":"Fecha de revisión tomada del nombre recibido; cajetines internos mantienen 02/07/2026 y algunos textos de plantilla.","sourceFileSha256":"b42eb027b7bc0b14c38d1d13514f4899b58a732aa8d0ba2ccf10fa2fc3192890"} | provisional | ["La planta general y algunos croquis de apoyo muestran dimensiones transversales distintas. Se usan el contorno de cimentación y los centros de pilares de la implantación general; sección de viga VC1 400 × 400 mm y vuelo a 1050 mm del eje según detalle.","La capa de mortero sobre la losa no tiene una referencia vertical inequívoca; no se duplica una capa independiente en esa losa."] | {"Cota inferior relativa (m)":0,"Cota superior relativa (m)":1.1,"Cero absoluto de visualización (m)":286.1,"Estado del cero absoluto":"Provisional","Criterio":"Las cotas relativas proceden del dibujo; la equivalencia absoluta no está confirmada."} | {"boundingBoxM":{"min":[40.540834,81.650828,1.1],"max":[40.991588,82.101582,2.2]},"extentsM":[0.450754,0.450754,1.1],"meshSurfaceM2":2.080001,"meshVolumeM3":0.176,"closedSolid":true,"basis":"Magnitudes de las mallas representadas, no cantidades certificadas de obra, compra o fabricación. Las partes pueden compartir superficies; no se suman como un despiece de materiales."} | {"profileId":"concrete_reinforced","name":"Hormigón armado · gris natural","materialName":"Hormigón armado · clase pendiente de confirmar","physicalMaterialStatus":"Clase no confirmada en la hoja de equipo","physicalMaterialSource":"Geometría de cimentación del fabricante; no se extrapola HA-30 de la nota de pedestales.","appearanceStatus":"criterio_visual","appearanceBasis":"Interpretación visual del material documental; el acabado, tono y parámetros PBR no son una especificación contractual.","note":"La apariencia gráfica no modifica ni confirma la especificación física del material."} | {"elementId":"found_0904_9050dd5e67c1f4","ifcGuid":"0D1HFPNBbQk9culKiEHqiE","ifcClass":"IfcFooting","buildingId":"process_plant","buildingName":"Zona de separación de aire","sourceDocumentId":"LHD2609-JG00100-20260904","sourceRepresentationKind":"foundation"} | {"layerId":"foundations","layerName":"Cimentaciones","role":"Cimentación industrial","basis":"Clasificación por función del elemento; no modifica las especificaciones documentales."} | {"profileId":"concrete_reinforced","name":"Hormigón armado · gris natural","status":"criterio_visual","basis":"Interpretación visual del material documental; el acabado, tono y parámetros PBR no son una especificación contractual.","physicalMaterialUnchanged":true} | 0.176 | Hormigón armado · clase pendiente de confirmar | Hormigón armado · gris natural | found_0904_9050dd5e67c1f4 | Geometría de cimentación del fabricante; no se extrapola HA-30 de la nota de pedestales. | Clase no confirmada en la hoja de equipo | concrete_reinforced | [0.666667,0.662745,0.619608] | 0.96 | Zona de separación de aire; BIM · Cimentaciones | 0.450754 | 0.450754 | 1.1 | 286.1 | 287.2 | F-LV-CONTAINER | ["LV-CONTAINER"] | [] | 13–13 | ["55EB/55F1","1DB82","1DE55"] | F-LV-CONTAINER/Cimentación y plataforma del módulo LV-CONTAINER · pilar KZ1 10 | foundation | Geometría de fabricante; implantación absoluta provisional | LV-CONTAINER | Cimentaciones de equipos y pedestales del fabricante · revisión recibida 04/09/2026 | 55EB/55F1, 1DB82, 1DE55 | 0 | 1.1 | 0.16 | Cotas relativas del dibujo. La equivalencia con un datum absoluto está pendiente. | Z del modelo = cota relativa + 1,10 m. Correspondencia provisional con 286,10 m; no es cota de obra confirmada. | Sección y contornos del fabricante; incidencias conservadas | 0.4 | 0.4 | La planta general y algunos croquis de apoyo muestran dimensiones transversales distintas. Se usan el contorno de cimentación y los centros de pilares de la implantación general; sección de viga VC1 400 × 400 mm y vuelo a 1050 mm del eje según detalle. / La capa de mortero sobre la losa no tiene una referencia vertical inequívoca; no se duplica una capa independiente en esa losa.
Cimentación y plataforma del módulo HV-CONTAINER · cuerpo de hormigón | Parcela industrial Jinhong | Cimentación industrial | Cimentaciones de equipos y pedestales del fabricante · revisión recibida 04/09/2026 | 12.437 | 6.1566 | 1 | 142.114 | 54.5569 | process_plant | Zona de separación de aire | {"name":"Hormigón armado · clase pendiente de confirmar","status":"Clase no confirmada en la hoja de equipo","source":"Geometría de cimentación del fabricante; no se extrapola HA-30 de la nota de pedestales."} | {"documented":[{"label":"Extensión local X","value":11.925,"unit":"m","source":"553E/5544, 1DB82, 1DE55","status":"derivada del contorno CAD"},{"label":"Extensión local Y","value":4.575,"unit":"m","source":"553E/5544, 1DB82, 1DE55","status":"derivada del contorno CAD"},{"label":"Cota inferior relativa adoptada","value":-1,"unit":"m","source":"14–14","status":"interpretación con conflicto conservado"},{"label":"Cota superior relativa adoptada","value":0,"unit":"m","source":"14–14","status":"documentada / separación por material"}],"geometry":[{"label":"Extensión de la malla en X","value":12.437001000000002,"unit":"m","source":"Geometría releída del IFC; datum absoluto de proceso provisional","status":"derivado"},{"label":"Extensión de la malla en Y","value":6.156595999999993,"unit":"m","source":"Geometría releída del IFC; datum absoluto de proceso provisional","status":"derivado"},{"label":"Extensión de la malla en Z","value":1.0,"unit":"m","source":"Geometría releída del IFC; datum absoluto de proceso provisional","status":"derivado"},{"label":"Cota inferior de visualización","value":285.1,"unit":"m","source":"Geometría releída del IFC; datum absoluto de proceso provisional","status":"derivado"},{"label":"Cota superior de visualización","value":286.1,"unit":"m","source":"Geometría releída del IFC; datum absoluto de proceso provisional","status":"derivado"}]} | {"documentId":"LHD2609-JG00100-20260904","title":"Cimentaciones de equipos y pedestales del fabricante · revisión recibida 04/09/2026","date":"2026-09-04","sheet":"14–14","fileName":"LHD2609-JG00100_20260904.dwg","revisionCaveat":"Fecha de revisión tomada del nombre recibido; cajetines internos mantienen 02/07/2026 y algunos textos de plantilla.","sourceFileSha256":"b42eb027b7bc0b14c38d1d13514f4899b58a732aa8d0ba2ccf10fa2fc3192890"} | provisional | ["La planta general y algunos croquis de apoyo muestran dimensiones transversales distintas. Se usan el contorno de cimentación y los centros de pilares de la implantación general; sección de viga VC1 400 × 400 mm y vuelo a 1050 mm del eje según detalle.","La capa de mortero sobre la losa no tiene una referencia vertical inequívoca; no se duplica una capa independiente en esa losa."] | {"Cota inferior relativa (m)":-1,"Cota superior relativa (m)":0,"Cero absoluto de visualización (m)":286.1,"Estado del cero absoluto":"Provisional","Criterio":"Las cotas relativas proceden del dibujo; la equivalencia absoluta no está confirmada."} | {"boundingBoxM":{"min":[54.575994,78.277628,0.1],"max":[67.012995,84.434224,1.1]},"extentsM":[12.437001,6.156596,1.0],"meshSurfaceM2":142.113738,"meshVolumeM3":54.55687,"closedSolid":true,"basis":"Magnitudes de las mallas representadas, no cantidades certificadas de obra, compra o fabricación. Las partes pueden compartir superficies; no se suman como un despiece de materiales."} | {"profileId":"concrete_reinforced","name":"Hormigón armado · gris natural","materialName":"Hormigón armado · clase pendiente de confirmar","physicalMaterialStatus":"Clase no confirmada en la hoja de equipo","physicalMaterialSource":"Geometría de cimentación del fabricante; no se extrapola HA-30 de la nota de pedestales.","appearanceStatus":"criterio_visual","appearanceBasis":"Interpretación visual del material documental; el acabado, tono y parámetros PBR no son una especificación contractual.","note":"La apariencia gráfica no modifica ni confirma la especificación física del material."} | {"elementId":"found_0904_3b311ea246324b","ifcGuid":"2v2PSNvEjHRgUZrRRZMuex","ifcClass":"IfcFooting","buildingId":"process_plant","buildingName":"Zona de separación de aire","sourceDocumentId":"LHD2609-JG00100-20260904","sourceRepresentationKind":"foundation"} | {"layerId":"foundations","layerName":"Cimentaciones","role":"Cimentación industrial","basis":"Clasificación por función del elemento; no modifica las especificaciones documentales."} | {"profileId":"concrete_reinforced","name":"Hormigón armado · gris natural","status":"criterio_visual","basis":"Interpretación visual del material documental; el acabado, tono y parámetros PBR no son una especificación contractual.","physicalMaterialUnchanged":true} | 54.5569 | Hormigón armado · clase pendiente de confirmar | Hormigón armado · gris natural | found_0904_3b311ea246324b | Geometría de cimentación del fabricante; no se extrapola HA-30 de la nota de pedestales. | Clase no confirmada en la hoja de equipo | concrete_reinforced | [0.666667,0.662745,0.619608] | 0.96 | Zona de separación de aire; BIM · Cimentaciones | 12.437 | 6.1566 | 1 | 285.1 | 286.1 | F-HV-CONTAINER | ["HV-CONTAINER"] | [] | 14–14 | ["553E/5544","1DB82","1DE55"] | F-HV-CONTAINER/Cimentación y plataforma del módulo HV-CONTAINER · cuerpo de hormigón | foundation | Geometría de fabricante; implantación absoluta provisional | HV-CONTAINER | Cimentaciones de equipos y pedestales del fabricante · revisión recibida 04/09/2026 | 553E/5544, 1DB82, 1DE55 | -1 | 0 | 54.5569 | Cotas relativas del dibujo. La equivalencia con un datum absoluto está pendiente. | Z del modelo = cota relativa + 1,10 m. Correspondencia provisional con 286,10 m; no es cota de obra confirmada. | Sección y contornos del fabricante; incidencias conservadas | 11.925 | 4.575 | La planta general y algunos croquis de apoyo muestran dimensiones transversales distintas. Se usan el contorno de cimentación y los centros de pilares de la implantación general; sección de viga VC1 400 × 400 mm y vuelo a 1050 mm del eje según detalle. / La capa de mortero sobre la losa no tiene una referencia vertical inequívoca; no se duplica una capa independiente en esa losa.
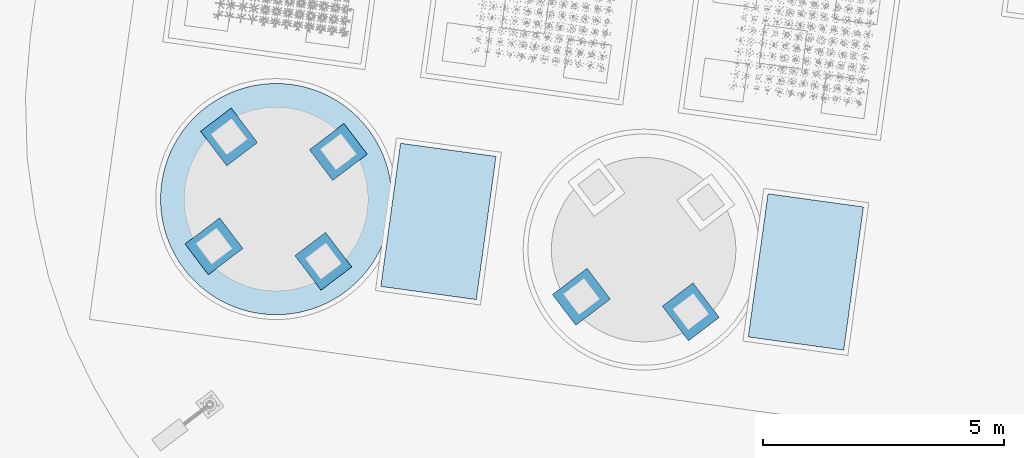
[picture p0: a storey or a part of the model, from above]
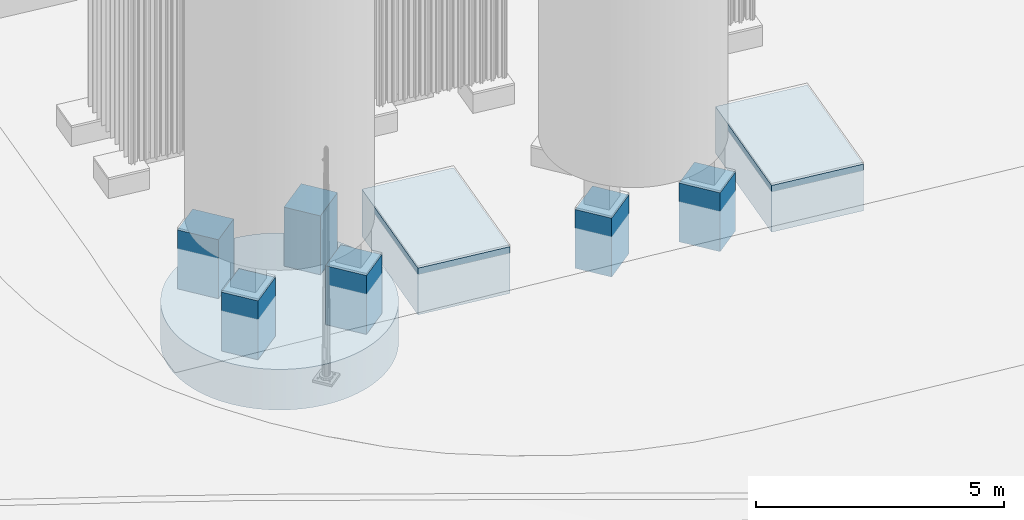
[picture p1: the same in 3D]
Properties of the parts of a building model (IFC4), part 75 of 134

# IfcFooting (214)
Name | In | Description = category = Categoria = Funcion | Document | ExtensionX (m) | ExtensionY (m) | ExtensionZ (m) | SuperficieDeLaMalla (m2) | VolumenGeometrico (m3) | buildingId | buildingName | material | dimensions | JH_InformacionBIM, source = DocumentoFuente | JH_InformacionBIM, status = EstadoDeInformacion | issues = IncidenciasPendientes | positioning = PosicionYEstado | geometryMetrics | materialAppearance | visualizationIdentity | classification | appearance | Volumen geométrico (m³) | JH_Trazabilidad, Material = name | Acabado de visualización = Acabado | Identificador | JH_EvidenciaDeMaterial, source | JH_EvidenciaDeMaterial, status | Perfil | ColorRGB | Rugosidad | Group | Extensión de la malla en X (m) | Extensión de la malla en Y (m) | Extensión de la malla en Z (m) = Espesor o altura real de sección (m) | Cota inferior de visualización (m) | Cota superior de visualización (m) | assemblyId = Conjunto de cimentación | equipmentIds | supportPositionIds | sectionRef = Sección de referencia | sourceCadHandles | stableElementKey | representationKind | geometryStatus | Equipos asociados | Documento de origen | Identificadores CAD de referencia | Cota inferior relativa (m) = Cota inferior relativa adoptada (m) | Cota superior relativa (m) = Cota superior relativa adoptada (m) | Área de planta (m²) | Referencia vertical | Implantación para visualización | Estado de la geometría | Extensión local X (m) | Extensión local Y (m) | Incidencias de origen
Cimentación y plataforma del módulo HV-CONTAINER · pilar KZ1 01 | Parcela industrial Jinhong | Cimentación industrial | Cimentaciones de equipos y pedestales del fabricante · revisión recibida 04/09/2026 | 0.450754 | 0.450754 | 1.1 | 2.08 | 0.176 | process_plant | Zona de separación de aire | {"name":"Hormigón armado · clase pendiente de confirmar","status":"Clase no confirmada en la hoja de equipo","source":"Geometría de cimentación del fabricante; no se extrapola HA-30 de la nota de pedestales."} | {"documented":[{"label":"Extensión local X","value":0.4,"unit":"m","source":"553E/5544, 1DB82, 1DE55","status":"derivada del contorno CAD"},{"label":"Extensión local Y","value":0.4,"unit":"m","source":"553E/5544, 1DB82, 1DE55","status":"derivada del contorno CAD"},{"label":"Cota inferior relativa adoptada","value":0,"unit":"m","source":"14–14","status":"interpretación con conflicto conservado"},{"label":"Cota superior relativa adoptada","value":1.1,"unit":"m","source":"14–14","status":"documentada / separación por material"}],"geometry":[{"label":"Extensión de la malla en X","value":0.4507539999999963,"unit":"m","source":"Geometría releída del IFC; datum absoluto de proceso provisional","status":"derivado"},{"label":"Extensión de la malla en Y","value":0.45075400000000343,"unit":"m","source":"Geometría releída del IFC; datum absoluto de proceso provisional","status":"derivado"},{"label":"Extensión de la malla en Z","value":1.1,"unit":"m","source":"Geometría releída del IFC; datum absoluto de proceso provisional","status":"derivado"},{"label":"Cota inferior de visualización","value":286.1,"unit":"m","source":"Geometría releída del IFC; datum absoluto de proceso provisional","status":"derivado"},{"label":"Cota superior de visualización","value":287.2,"unit":"m","source":"Geometría releída del IFC; datum absoluto de proceso provisional","status":"derivado"}]} | {"documentId":"LHD2609-JG00100-20260904","title":"Cimentaciones de equipos y pedestales del fabricante · revisión recibida 04/09/2026","date":"2026-09-04","sheet":"14–14","fileName":"LHD2609-JG00100_20260904.dwg","revisionCaveat":"Fecha de revisión tomada del nombre recibido; cajetines internos mantienen 02/07/2026 y algunos textos de plantilla.","sourceFileSha256":"b42eb027b7bc0b14c38d1d13514f4899b58a732aa8d0ba2ccf10fa2fc3192890"} | provisional | ["La planta general y algunos croquis de apoyo muestran dimensiones transversales distintas. Se usan el contorno de cimentación y los centros de pilares de la implantación general; sección de viga VC1 400 × 400 mm y vuelo a 1050 mm del eje según detalle.","La capa de mortero sobre la losa no tiene una referencia vertical inequívoca; no se duplica una capa independiente en esa losa."] | {"Cota inferior relativa (m)":0,"Cota superior relativa (m)":1.1,"Cero absoluto de visualización (m)":286.1,"Estado del cero absoluto":"Provisional","Criterio":"Las cotas relativas proceden del dibujo; la equivalencia absoluta no está confirmada."} | {"boundingBoxM":{"min":[54.914059,80.103721,1.1],"max":[55.364813,80.554475,2.2]},"extentsM":[0.450754,0.450754,1.1],"meshSurfaceM2":2.079998,"meshVolumeM3":0.176,"closedSolid":true,"basis":"Magnitudes de las mallas representadas, no cantidades certificadas de obra, compra o fabricación. Las partes pueden compartir superficies; no se suman como un despiece de materiales."} | {"profileId":"concrete_reinforced","name":"Hormigón armado · gris natural","materialName":"Hormigón armado · clase pendiente de confirmar","physicalMaterialStatus":"Clase no confirmada en la hoja de equipo","physicalMaterialSource":"Geometría de cimentación del fabricante; no se extrapola HA-30 de la nota de pedestales.","appearanceStatus":"criterio_visual","appearanceBasis":"Interpretación visual del material documental; el acabado, tono y parámetros PBR no son una especificación contractual.","note":"La apariencia gráfica no modifica ni confirma la especificación física del material."} | {"elementId":"found_0904_d47b7eba926e93","ifcGuid":"3_ZVjY1o9PKgrxLnCfOmmV","ifcClass":"IfcFooting","buildingId":"process_plant","buildingName":"Zona de separación de aire","sourceDocumentId":"LHD2609-JG00100-20260904","sourceRepresentationKind":"foundation"} | {"layerId":"foundations","layerName":"Cimentaciones","role":"Cimentación industrial","basis":"Clasificación por función del elemento; no modifica las especificaciones documentales."} | {"profileId":"concrete_reinforced","name":"Hormigón armado · gris natural","status":"criterio_visual","basis":"Interpretación visual del material documental; el acabado, tono y parámetros PBR no son una especificación contractual.","physicalMaterialUnchanged":true} | 0.176 | Hormigón armado · clase pendiente de confirmar | Hormigón armado · gris natural | found_0904_d47b7eba926e93 | Geometría de cimentación del fabricante; no se extrapola HA-30 de la nota de pedestales. | Clase no confirmada en la hoja de equipo | concrete_reinforced | [0.666667,0.662745,0.619608] | 0.96 | Zona de separación de aire; BIM · Cimentaciones | 0.450754 | 0.450754 | 1.1 | 286.1 | 287.2 | F-HV-CONTAINER | ["HV-CONTAINER"] | [] | 14–14 | ["553E/5544","1DB82","1DE55"] | F-HV-CONTAINER/Cimentación y plataforma del módulo HV-CONTAINER · pilar KZ1 01 | foundation | Geometría de fabricante; implantación absoluta provisional | HV-CONTAINER | Cimentaciones de equipos y pedestales del fabricante · revisión recibida 04/09/2026 | 553E/5544, 1DB82, 1DE55 | 0 | 1.1 | 0.16 | Cotas relativas del dibujo. La equivalencia con un datum absoluto está pendiente. | Z del modelo = cota relativa + 1,10 m. Correspondencia provisional con 286,10 m; no es cota de obra confirmada. | Sección y contornos del fabricante; incidencias conservadas | 0.4 | 0.4 | La planta general y algunos croquis de apoyo muestran dimensiones transversales distintas. Se usan el contorno de cimentación y los centros de pilares de la implantación general; sección de viga VC1 400 × 400 mm y vuelo a 1050 mm del eje según detalle. / La capa de mortero sobre la losa no tiene una referencia vertical inequívoca; no se duplica una capa independiente en esa losa.
Cimentación y plataforma del módulo HV-CONTAINER · pilar KZ1 02 | Parcela industrial Jinhong | Cimentación industrial | Cimentaciones de equipos y pedestales del fabricante · revisión recibida 04/09/2026 | 0.450754 | 0.450754 | 1.1 | 2.08 | 0.176 | process_plant | Zona de separación de aire | {"name":"Hormigón armado · clase pendiente de confirmar","status":"Clase no confirmada en la hoja de equipo","source":"Geometría de cimentación del fabricante; no se extrapola HA-30 de la nota de pedestales."} | {"documented":[{"label":"Extensión local X","value":0.4,"unit":"m","source":"553E/5544, 1DB82, 1DE55","status":"derivada del contorno CAD"},{"label":"Extensión local Y","value":0.4,"unit":"m","source":"553E/5544, 1DB82, 1DE55","status":"derivada del contorno CAD"},{"label":"Cota inferior relativa adoptada","value":0,"unit":"m","source":"14–14","status":"interpretación con conflicto conservado"},{"label":"Cota superior relativa adoptada","value":1.1,"unit":"m","source":"14–14","status":"documentada / separación por material"}],"geometry":[{"label":"Extensión de la malla en X","value":0.45075400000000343,"unit":"m","source":"Geometría releída del IFC; datum absoluto de proceso provisional","status":"derivado"},{"label":"Extensión de la malla en Y","value":0.45075400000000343,"unit":"m","source":"Geometría releída del IFC; datum absoluto de proceso provisional","status":"derivado"},{"label":"Extensión de la malla en Z","value":1.1,"unit":"m","source":"Geometría releída del IFC; datum absoluto de proceso provisional","status":"derivado"},{"label":"Cota inferior de visualización","value":286.1,"unit":"m","source":"Geometría releída del IFC; datum absoluto de proceso provisional","status":"derivado"},{"label":"Cota superior de visualización","value":287.2,"unit":"m","source":"Geometría releída del IFC; datum absoluto de proceso provisional","status":"derivado"}]} | {"documentId":"LHD2609-JG00100-20260904","title":"Cimentaciones de equipos y pedestales del fabricante · revisión recibida 04/09/2026","date":"2026-09-04","sheet":"14–14","fileName":"LHD2609-JG00100_20260904.dwg","revisionCaveat":"Fecha de revisión tomada del nombre recibido; cajetines internos mantienen 02/07/2026 y algunos textos de plantilla.","sourceFileSha256":"b42eb027b7bc0b14c38d1d13514f4899b58a732aa8d0ba2ccf10fa2fc3192890"} | provisional | ["La planta general y algunos croquis de apoyo muestran dimensiones transversales distintas. Se usan el contorno de cimentación y los centros de pilares de la implantación general; sección de viga VC1 400 × 400 mm y vuelo a 1050 mm del eje según detalle.","La capa de mortero sobre la losa no tiene una referencia vertical inequívoca; no se duplica una capa independiente en esa losa."] | {"Cota inferior relativa (m)":0,"Cota superior relativa (m)":1.1,"Cero absoluto de visualización (m)":286.1,"Estado del cero absoluto":"Provisional","Criterio":"Las cotas relativas proceden del dibujo; la equivalencia absoluta no está confirmada."} | {"boundingBoxM":{"min":[57.205008,79.788749,1.1],"max":[57.655762,80.239503,2.2]},"extentsM":[0.450754,0.450754,1.1],"meshSurfaceM2":2.080001,"meshVolumeM3":0.176,"closedSolid":true,"basis":"Magnitudes de las mallas representadas, no cantidades certificadas de obra, compra o fabricación. Las partes pueden compartir superficies; no se suman como un despiece de materiales."} | {"profileId":"concrete_reinforced","name":"Hormigón armado · gris natural","materialName":"Hormigón armado · clase pendiente de confirmar","physicalMaterialStatus":"Clase no confirmada en la hoja de equipo","physicalMaterialSource":"Geometría de cimentación del fabricante; no se extrapola HA-30 de la nota de pedestales.","appearanceStatus":"criterio_visual","appearanceBasis":"Interpretación visual del material documental; el acabado, tono y parámetros PBR no son una especificación contractual.","note":"La apariencia gráfica no modifica ni confirma la especificación física del material."} | {"elementId":"found_0904_41f2fa27380188","ifcGuid":"0RfIu8wX9M3v9_CHdWGOA0","ifcClass":"IfcFooting","buildingId":"process_plant","buildingName":"Zona de separación de aire","sourceDocumentId":"LHD2609-JG00100-20260904","sourceRepresentationKind":"foundation"} | {"layerId":"foundations","layerName":"Cimentaciones","role":"Cimentación industrial","basis":"Clasificación por función del elemento; no modifica las especificaciones documentales."} | {"profileId":"concrete_reinforced","name":"Hormigón armado · gris natural","status":"criterio_visual","basis":"Interpretación visual del material documental; el acabado, tono y parámetros PBR no son una especificación contractual.","physicalMaterialUnchanged":true} | 0.176 | Hormigón armado · clase pendiente de confirmar | Hormigón armado · gris natural | found_0904_41f2fa27380188 | Geometría de cimentación del fabricante; no se extrapola HA-30 de la nota de pedestales. | Clase no confirmada en la hoja de equipo | concrete_reinforced | [0.666667,0.662745,0.619608] | 0.96 | Zona de separación de aire; BIM · Cimentaciones | 0.450754 | 0.450754 | 1.1 | 286.1 | 287.2 | F-HV-CONTAINER | ["HV-CONTAINER"] | [] | 14–14 | ["553E/5544","1DB82","1DE55"] | F-HV-CONTAINER/Cimentación y plataforma del módulo HV-CONTAINER · pilar KZ1 02 | foundation | Geometría de fabricante; implantación absoluta provisional | HV-CONTAINER | Cimentaciones de equipos y pedestales del fabricante · revisión recibida 04/09/2026 | 553E/5544, 1DB82, 1DE55 | 0 | 1.1 | 0.16 | Cotas relativas del dibujo. La equivalencia con un datum absoluto está pendiente. | Z del modelo = cota relativa + 1,10 m. Correspondencia provisional con 286,10 m; no es cota de obra confirmada. | Sección y contornos del fabricante; incidencias conservadas | 0.4 | 0.4 | La planta general y algunos croquis de apoyo muestran dimensiones transversales distintas. Se usan el contorno de cimentación y los centros de pilares de la implantación general; sección de viga VC1 400 × 400 mm y vuelo a 1050 mm del eje según detalle. / La capa de mortero sobre la losa no tiene una referencia vertical inequívoca; no se duplica una capa independiente en esa losa.
Cimentación y plataforma del módulo HV-CONTAINER · pilar KZ1 03 | Parcela industrial Jinhong | Cimentación industrial | Cimentaciones de equipos y pedestales del fabricante · revisión recibida 04/09/2026 | 0.450754 | 0.450754 | 1.1 | 2.08 | 0.176 | process_plant | Zona de separación de aire | {"name":"Hormigón armado · clase pendiente de confirmar","status":"Clase no confirmada en la hoja de equipo","source":"Geometría de cimentación del fabricante; no se extrapola HA-30 de la nota de pedestales."} | {"documented":[{"label":"Extensión local X","value":0.4,"unit":"m","source":"553E/5544, 1DB82, 1DE55","status":"derivada del contorno CAD"},{"label":"Extensión local Y","value":0.4,"unit":"m","source":"553E/5544, 1DB82, 1DE55","status":"derivada del contorno CAD"},{"label":"Cota inferior relativa adoptada","value":0,"unit":"m","source":"14–14","status":"interpretación con conflicto conservado"},{"label":"Cota superior relativa adoptada","value":1.1,"unit":"m","source":"14–14","status":"documentada / separación por material"}],"geometry":[{"label":"Extensión de la malla en X","value":0.4507539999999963,"unit":"m","source":"Geometría releída del IFC; datum absoluto de proceso provisional","status":"derivado"},{"label":"Extensión de la malla en Y","value":0.45075400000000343,"unit":"m","source":"Geometría releída del IFC; datum absoluto de proceso provisional","status":"derivado"},{"label":"Extensión de la malla en Z","value":1.1,"unit":"m","source":"Geometría releída del IFC; datum absoluto de proceso provisional","status":"derivado"},{"label":"Cota inferior de visualización","value":286.1,"unit":"m","source":"Geometría releída del IFC; datum absoluto de proceso provisional","status":"derivado"},{"label":"Cota superior de visualización","value":287.2,"unit":"m","source":"Geometría releída del IFC; datum absoluto de proceso provisional","status":"derivado"}]} | {"documentId":"LHD2609-JG00100-20260904","title":"Cimentaciones de equipos y pedestales del fabricante · revisión recibida 04/09/2026","date":"2026-09-04","sheet":"14–14","fileName":"LHD2609-JG00100_20260904.dwg","revisionCaveat":"Fecha de revisión tomada del nombre recibido; cajetines internos mantienen 02/07/2026 y algunos textos de plantilla.","sourceFileSha256":"b42eb027b7bc0b14c38d1d13514f4899b58a732aa8d0ba2ccf10fa2fc3192890"} | provisional | ["La planta general y algunos croquis de apoyo muestran dimensiones transversales distintas. Se usan el contorno de cimentación y los centros de pilares de la implantación general; sección de viga VC1 400 × 400 mm y vuelo a 1050 mm del eje según detalle.","La capa de mortero sobre la losa no tiene una referencia vertical inequívoca; no se duplica una capa independiente en esa losa."] | {"Cota inferior relativa (m)":0,"Cota superior relativa (m)":1.1,"Cero absoluto de visualización (m)":286.1,"Estado del cero absoluto":"Provisional","Criterio":"Las cotas relativas proceden del dibujo; la equivalencia absoluta no está confirmada."} | {"boundingBoxM":{"min":[59.495958,79.473778,1.1],"max":[59.946712,79.924532,2.2]},"extentsM":[0.450754,0.450754,1.1],"meshSurfaceM2":2.080001,"meshVolumeM3":0.176,"closedSolid":true,"basis":"Magnitudes de las mallas representadas, no cantidades certificadas de obra, compra o fabricación. Las partes pueden compartir superficies; no se suman como un despiece de materiales."} | {"profileId":"concrete_reinforced","name":"Hormigón armado · gris natural","materialName":"Hormigón armado · clase pendiente de confirmar","physicalMaterialStatus":"Clase no confirmada en la hoja de equipo","physicalMaterialSource":"Geometría de cimentación del fabricante; no se extrapola HA-30 de la nota de pedestales.","appearanceStatus":"criterio_visual","appearanceBasis":"Interpretación visual del material documental; el acabado, tono y parámetros PBR no son una especificación contractual.","note":"La apariencia gráfica no modifica ni confirma la especificación física del material."} | {"elementId":"found_0904_5fb13cd93ff0a2","ifcGuid":"21azDgMjvIZBqb6ycJfyCb","ifcClass":"IfcFooting","buildingId":"process_plant","buildingName":"Zona de separación de aire","sourceDocumentId":"LHD2609-JG00100-20260904","sourceRepresentationKind":"foundation"} | {"layerId":"foundations","layerName":"Cimentaciones","role":"Cimentación industrial","basis":"Clasificación por función del elemento; no modifica las especificaciones documentales."} | {"profileId":"concrete_reinforced","name":"Hormigón armado · gris natural","status":"criterio_visual","basis":"Interpretación visual del material documental; el acabado, tono y parámetros PBR no son una especificación contractual.","physicalMaterialUnchanged":true} | 0.176 | Hormigón armado · clase pendiente de confirmar | Hormigón armado · gris natural | found_0904_5fb13cd93ff0a2 | Geometría de cimentación del fabricante; no se extrapola HA-30 de la nota de pedestales. | Clase no confirmada en la hoja de equipo | concrete_reinforced | [0.666667,0.662745,0.619608] | 0.96 | Zona de separación de aire; BIM · Cimentaciones | 0.450754 | 0.450754 | 1.1 | 286.1 | 287.2 | F-HV-CONTAINER | ["HV-CONTAINER"] | [] | 14–14 | ["553E/5544","1DB82","1DE55"] | F-HV-CONTAINER/Cimentación y plataforma del módulo HV-CONTAINER · pilar KZ1 03 | foundation | Geometría de fabricante; implantación absoluta provisional | HV-CONTAINER | Cimentaciones de equipos y pedestales del fabricante · revisión recibida 04/09/2026 | 553E/5544, 1DB82, 1DE55 | 0 | 1.1 | 0.16 | Cotas relativas del dibujo. La equivalencia con un datum absoluto está pendiente. | Z del modelo = cota relativa + 1,10 m. Correspondencia provisional con 286,10 m; no es cota de obra confirmada. | Sección y contornos del fabricante; incidencias conservadas | 0.4 | 0.4 | La planta general y algunos croquis de apoyo muestran dimensiones transversales distintas. Se usan el contorno de cimentación y los centros de pilares de la implantación general; sección de viga VC1 400 × 400 mm y vuelo a 1050 mm del eje según detalle. / La capa de mortero sobre la losa no tiene una referencia vertical inequívoca; no se duplica una capa independiente en esa losa.
Cimentación y plataforma del módulo HV-CONTAINER · pilar KZ1 04 | Parcela industrial Jinhong | Cimentación industrial | Cimentaciones de equipos y pedestales del fabricante · revisión recibida 04/09/2026 | 0.450754 | 0.450754 | 1.1 | 2.08 | 0.176 | process_plant | Zona de separación de aire | {"name":"Hormigón armado · clase pendiente de confirmar","status":"Clase no confirmada en la hoja de equipo","source":"Geometría de cimentación del fabricante; no se extrapola HA-30 de la nota de pedestales."} | {"documented":[{"label":"Extensión local X","value":0.4,"unit":"m","source":"553E/5544, 1DB82, 1DE55","status":"derivada del contorno CAD"},{"label":"Extensión local Y","value":0.4,"unit":"m","source":"553E/5544, 1DB82, 1DE55","status":"derivada del contorno CAD"},{"label":"Cota inferior relativa adoptada","value":0,"unit":"m","source":"14–14","status":"interpretación con conflicto conservado"},{"label":"Cota superior relativa adoptada","value":1.1,"unit":"m","source":"14–14","status":"documentada / separación por material"}],"geometry":[{"label":"Extensión de la malla en X","value":0.45075400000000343,"unit":"m","source":"Geometría releída del IFC; datum absoluto de proceso provisional","status":"derivado"},{"label":"Extensión de la malla en Y","value":0.45075400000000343,"unit":"m","source":"Geometría releída del IFC; datum absoluto de proceso provisional","status":"derivado"},{"label":"Extensión de la malla en Z","value":1.1,"unit":"m","source":"Geometría releída del IFC; datum absoluto de proceso provisional","status":"derivado"},{"label":"Cota inferior de visualización","value":286.1,"unit":"m","source":"Geometría releída del IFC; datum absoluto de proceso provisional","status":"derivado"},{"label":"Cota superior de visualización","value":287.2,"unit":"m","source":"Geometría releída del IFC; datum absoluto de proceso provisional","status":"derivado"}]} | {"documentId":"LHD2609-JG00100-20260904","title":"Cimentaciones de equipos y pedestales del fabricante · revisión recibida 04/09/2026","date":"2026-09-04","sheet":"14–14","fileName":"LHD2609-JG00100_20260904.dwg","revisionCaveat":"Fecha de revisión tomada del nombre recibido; cajetines internos mantienen 02/07/2026 y algunos textos de plantilla.","sourceFileSha256":"b42eb027b7bc0b14c38d1d13514f4899b58a732aa8d0ba2ccf10fa2fc3192890"} | provisional | ["La planta general y algunos croquis de apoyo muestran dimensiones transversales distintas. Se usan el contorno de cimentación y los centros de pilares de la implantación general; sección de viga VC1 400 × 400 mm y vuelo a 1050 mm del eje según detalle.","La capa de mortero sobre la losa no tiene una referencia vertical inequívoca; no se duplica una capa independiente en esa losa."] | {"Cota inferior relativa (m)":0,"Cota superior relativa (m)":1.1,"Cero absoluto de visualización (m)":286.1,"Estado del cero absoluto":"Provisional","Criterio":"Las cotas relativas proceden del dibujo; la equivalencia absoluta no está confirmada."} | {"boundingBoxM":{"min":[61.786907,79.158806,1.1],"max":[62.237661,79.60956,2.2]},"extentsM":[0.450754,0.450754,1.1],"meshSurfaceM2":2.08,"meshVolumeM3":0.176,"closedSolid":true,"basis":"Magnitudes de las mallas representadas, no cantidades certificadas de obra, compra o fabricación. Las partes pueden compartir superficies; no se suman como un despiece de materiales."} | {"profileId":"concrete_reinforced","name":"Hormigón armado · gris natural","materialName":"Hormigón armado · clase pendiente de confirmar","physicalMaterialStatus":"Clase no confirmada en la hoja de equipo","physicalMaterialSource":"Geometría de cimentación del fabricante; no se extrapola HA-30 de la nota de pedestales.","appearanceStatus":"criterio_visual","appearanceBasis":"Interpretación visual del material documental; el acabado, tono y parámetros PBR no son una especificación contractual.","note":"La apariencia gráfica no modifica ni confirma la especificación física del material."} | {"elementId":"found_0904_2a52ebeeeeddd3","ifcGuid":"2rchb5rOXVv8AUHX7WSqQ_","ifcClass":"IfcFooting","buildingId":"process_plant","buildingName":"Zona de separación de aire","sourceDocumentId":"LHD2609-JG00100-20260904","sourceRepresentationKind":"foundation"} | {"layerId":"foundations","layerName":"Cimentaciones","role":"Cimentación industrial","basis":"Clasificación por función del elemento; no modifica las especificaciones documentales."} | {"profileId":"concrete_reinforced","name":"Hormigón armado · gris natural","status":"criterio_visual","basis":"Interpretación visual del material documental; el acabado, tono y parámetros PBR no son una especificación contractual.","physicalMaterialUnchanged":true} | 0.176 | Hormigón armado · clase pendiente de confirmar | Hormigón armado · gris natural | found_0904_2a52ebeeeeddd3 | Geometría de cimentación del fabricante; no se extrapola HA-30 de la nota de pedestales. | Clase no confirmada en la hoja de equipo | concrete_reinforced | [0.666667,0.662745,0.619608] | 0.96 | Zona de separación de aire; BIM · Cimentaciones | 0.450754 | 0.450754 | 1.1 | 286.1 | 287.2 | F-HV-CONTAINER | ["HV-CONTAINER"] | [] | 14–14 | ["553E/5544","1DB82","1DE55"] | F-HV-CONTAINER/Cimentación y plataforma del módulo HV-CONTAINER · pilar KZ1 04 | foundation | Geometría de fabricante; implantación absoluta provisional | HV-CONTAINER | Cimentaciones de equipos y pedestales del fabricante · revisión recibida 04/09/2026 | 553E/5544, 1DB82, 1DE55 | 0 | 1.1 | 0.16 | Cotas relativas del dibujo. La equivalencia con un datum absoluto está pendiente. | Z del modelo = cota relativa + 1,10 m. Correspondencia provisional con 286,10 m; no es cota de obra confirmada. | Sección y contornos del fabricante; incidencias conservadas | 0.4 | 0.4 | La planta general y algunos croquis de apoyo muestran dimensiones transversales distintas. Se usan el contorno de cimentación y los centros de pilares de la implantación general; sección de viga VC1 400 × 400 mm y vuelo a 1050 mm del eje según detalle. / La capa de mortero sobre la losa no tiene una referencia vertical inequívoca; no se duplica una capa independiente en esa losa.
Cimentación y plataforma del módulo HV-CONTAINER · pilar KZ1 05 | Parcela industrial Jinhong | Cimentación industrial | Cimentaciones de equipos y pedestales del fabricante · revisión recibida 04/09/2026 | 0.450753 | 0.450754 | 1.1 | 2.08 | 0.176 | process_plant | Zona de separación de aire | {"name":"Hormigón armado · clase pendiente de confirmar","status":"Clase no confirmada en la hoja de equipo","source":"Geometría de cimentación del fabricante; no se extrapola HA-30 de la nota de pedestales."} | {"documented":[{"label":"Extensión local X","value":0.4,"unit":"m","source":"553E/5544, 1DB82, 1DE55","status":"derivada del contorno CAD"},{"label":"Extensión local Y","value":0.4,"unit":"m","source":"553E/5544, 1DB82, 1DE55","status":"derivada del contorno CAD"},{"label":"Cota inferior relativa adoptada","value":0,"unit":"m","source":"14–14","status":"interpretación con conflicto conservado"},{"label":"Cota superior relativa adoptada","value":1.1,"unit":"m","source":"14–14","status":"documentada / separación por material"}],"geometry":[{"label":"Extensión de la malla en X","value":0.45075300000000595,"unit":"m","source":"Geometría releída del IFC; datum absoluto de proceso provisional","status":"derivado"},{"label":"Extensión de la malla en Y","value":0.45075400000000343,"unit":"m","source":"Geometría releída del IFC; datum absoluto de proceso provisional","status":"derivado"},{"label":"Extensión de la malla en Z","value":1.1,"unit":"m","source":"Geometría releída del IFC; datum absoluto de proceso provisional","status":"derivado"},{"label":"Cota inferior de visualización","value":286.1,"unit":"m","source":"Geometría releída del IFC; datum absoluto de proceso provisional","status":"derivado"},{"label":"Cota superior de visualización","value":287.2,"unit":"m","source":"Geometría releída del IFC; datum absoluto de proceso provisional","status":"derivado"}]} | {"documentId":"LHD2609-JG00100-20260904","title":"Cimentaciones de equipos y pedestales del fabricante · revisión recibida 04/09/2026","date":"2026-09-04","sheet":"14–14","fileName":"LHD2609-JG00100_20260904.dwg","revisionCaveat":"Fecha de revisión tomada del nombre recibido; cajetines internos mantienen 02/07/2026 y algunos textos de plantilla.","sourceFileSha256":"b42eb027b7bc0b14c38d1d13514f4899b58a732aa8d0ba2ccf10fa2fc3192890"} | provisional | ["La planta general y algunos croquis de apoyo muestran dimensiones transversales distintas. Se usan el contorno de cimentación y los centros de pilares de la implantación general; sección de viga VC1 400 × 400 mm y vuelo a 1050 mm del eje según detalle.","La capa de mortero sobre la losa no tiene una referencia vertical inequívoca; no se duplica una capa independiente en esa losa."] | {"Cota inferior relativa (m)":0,"Cota superior relativa (m)":1.1,"Cero absoluto de visualización (m)":286.1,"Estado del cero absoluto":"Provisional","Criterio":"Las cotas relativas proceden del dibujo; la equivalencia absoluta no está confirmada."} | {"boundingBoxM":{"min":[64.077857,78.843835,1.1],"max":[64.52861,79.294589,2.2]},"extentsM":[0.450753,0.450754,1.1],"meshSurfaceM2":2.079999,"meshVolumeM3":0.176,"closedSolid":true,"basis":"Magnitudes de las mallas representadas, no cantidades certificadas de obra, compra o fabricación. Las partes pueden compartir superficies; no se suman como un despiece de materiales."} | {"profileId":"concrete_reinforced","name":"Hormigón armado · gris natural","materialName":"Hormigón armado · clase pendiente de confirmar","physicalMaterialStatus":"Clase no confirmada en la hoja de equipo","physicalMaterialSource":"Geometría de cimentación del fabricante; no se extrapola HA-30 de la nota de pedestales.","appearanceStatus":"criterio_visual","appearanceBasis":"Interpretación visual del material documental; el acabado, tono y parámetros PBR no son una especificación contractual.","note":"La apariencia gráfica no modifica ni confirma la especificación física del material."} | {"elementId":"found_0904_d1201ff518db4f","ifcGuid":"2Zx74rOwzKcgJv$ksHtbwn","ifcClass":"IfcFooting","buildingId":"process_plant","buildingName":"Zona de separación de aire","sourceDocumentId":"LHD2609-JG00100-20260904","sourceRepresentationKind":"foundation"} | {"layerId":"foundations","layerName":"Cimentaciones","role":"Cimentación industrial","basis":"Clasificación por función del elemento; no modifica las especificaciones documentales."} | {"profileId":"concrete_reinforced","name":"Hormigón armado · gris natural","status":"criterio_visual","basis":"Interpretación visual del material documental; el acabado, tono y parámetros PBR no son una especificación contractual.","physicalMaterialUnchanged":true} | 0.176 | Hormigón armado · clase pendiente de confirmar | Hormigón armado · gris natural | found_0904_d1201ff518db4f | Geometría de cimentación del fabricante; no se extrapola HA-30 de la nota de pedestales. | Clase no confirmada en la hoja de equipo | concrete_reinforced | [0.666667,0.662745,0.619608] | 0.96 | Zona de separación de aire; BIM · Cimentaciones | 0.450753 | 0.450754 | 1.1 | 286.1 | 287.2 | F-HV-CONTAINER | ["HV-CONTAINER"] | [] | 14–14 | ["553E/5544","1DB82","1DE55"] | F-HV-CONTAINER/Cimentación y plataforma del módulo HV-CONTAINER · pilar KZ1 05 | foundation | Geometría de fabricante; implantación absoluta provisional | HV-CONTAINER | Cimentaciones de equipos y pedestales del fabricante · revisión recibida 04/09/2026 | 553E/5544, 1DB82, 1DE55 | 0 | 1.1 | 0.16 | Cotas relativas del dibujo. La equivalencia con un datum absoluto está pendiente. | Z del modelo = cota relativa + 1,10 m. Correspondencia provisional con 286,10 m; no es cota de obra confirmada. | Sección y contornos del fabricante; incidencias conservadas | 0.4 | 0.4 | La planta general y algunos croquis de apoyo muestran dimensiones transversales distintas. Se usan el contorno de cimentación y los centros de pilares de la implantación general; sección de viga VC1 400 × 400 mm y vuelo a 1050 mm del eje según detalle. / La capa de mortero sobre la losa no tiene una referencia vertical inequívoca; no se duplica una capa independiente en esa losa.
Cimentación y plataforma del módulo HV-CONTAINER · pilar KZ1 06 | Parcela industrial Jinhong | Cimentación industrial | Cimentaciones de equipos y pedestales del fabricante · revisión recibida 04/09/2026 | 0.450753 | 0.450754 | 1.1 | 2.08 | 0.176 | process_plant | Zona de separación de aire | {"name":"Hormigón armado · clase pendiente de confirmar","status":"Clase no confirmada en la hoja de equipo","source":"Geometría de cimentación del fabricante; no se extrapola HA-30 de la nota de pedestales."} | {"documented":[{"label":"Extensión local X","value":0.4,"unit":"m","source":"553E/5544, 1DB82, 1DE55","status":"derivada del contorno CAD"},{"label":"Extensión local Y","value":0.4,"unit":"m","source":"553E/5544, 1DB82, 1DE55","status":"derivada del contorno CAD"},{"label":"Cota inferior relativa adoptada","value":0,"unit":"m","source":"14–14","status":"interpretación con conflicto conservado"},{"label":"Cota superior relativa adoptada","value":1.1,"unit":"m","source":"14–14","status":"documentada / separación por material"}],"geometry":[{"label":"Extensión de la malla en X","value":0.45075299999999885,"unit":"m","source":"Geometría releída del IFC; datum absoluto de proceso provisional","status":"derivado"},{"label":"Extensión de la malla en Y","value":0.45075400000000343,"unit":"m","source":"Geometría releída del IFC; datum absoluto de proceso provisional","status":"derivado"},{"label":"Extensión de la malla en Z","value":1.1,"unit":"m","source":"Geometría releída del IFC; datum absoluto de proceso provisional","status":"derivado"},{"label":"Cota inferior de visualización","value":286.1,"unit":"m","source":"Geometría releída del IFC; datum absoluto de proceso provisional","status":"derivado"},{"label":"Cota superior de visualización","value":287.2,"unit":"m","source":"Geometría releída del IFC; datum absoluto de proceso provisional","status":"derivado"}]} | {"documentId":"LHD2609-JG00100-20260904","title":"Cimentaciones de equipos y pedestales del fabricante · revisión recibida 04/09/2026","date":"2026-09-04","sheet":"14–14","fileName":"LHD2609-JG00100_20260904.dwg","revisionCaveat":"Fecha de revisión tomada del nombre recibido; cajetines internos mantienen 02/07/2026 y algunos textos de plantilla.","sourceFileSha256":"b42eb027b7bc0b14c38d1d13514f4899b58a732aa8d0ba2ccf10fa2fc3192890"} | provisional | ["La planta general y algunos croquis de apoyo muestran dimensiones transversales distintas. Se usan el contorno de cimentación y los centros de pilares de la implantación general; sección de viga VC1 400 × 400 mm y vuelo a 1050 mm del eje según detalle.","La capa de mortero sobre la losa no tiene una referencia vertical inequívoca; no se duplica una capa independiente en esa losa."] | {"Cota inferior relativa (m)":0,"Cota superior relativa (m)":1.1,"Cero absoluto de visualización (m)":286.1,"Estado del cero absoluto":"Provisional","Criterio":"Las cotas relativas proceden del dibujo; la equivalencia absoluta no está confirmada."} | {"boundingBoxM":{"min":[55.315861,83.026229,1.1],"max":[55.766614,83.476983,2.2]},"extentsM":[0.450753,0.450754,1.1],"meshSurfaceM2":2.079999,"meshVolumeM3":0.176,"closedSolid":true,"basis":"Magnitudes de las mallas representadas, no cantidades certificadas de obra, compra o fabricación. Las partes pueden compartir superficies; no se suman como un despiece de materiales."} | {"profileId":"concrete_reinforced","name":"Hormigón armado · gris natural","materialName":"Hormigón armado · clase pendiente de confirmar","physicalMaterialStatus":"Clase no confirmada en la hoja de equipo","physicalMaterialSource":"Geometría de cimentación del fabricante; no se extrapola HA-30 de la nota de pedestales.","appearanceStatus":"criterio_visual","appearanceBasis":"Interpretación visual del material documental; el acabado, tono y parámetros PBR no son una especificación contractual.","note":"La apariencia gráfica no modifica ni confirma la especificación física del material."} | {"elementId":"found_0904_075ddcfd9c66be","ifcGuid":"1sld$DagrKag2TSv_wurZQ","ifcClass":"IfcFooting","buildingId":"process_plant","buildingName":"Zona de separación de aire","sourceDocumentId":"LHD2609-JG00100-20260904","sourceRepresentationKind":"foundation"} | {"layerId":"foundations","layerName":"Cimentaciones","role":"Cimentación industrial","basis":"Clasificación por función del elemento; no modifica las especificaciones documentales."} | {"profileId":"concrete_reinforced","name":"Hormigón armado · gris natural","status":"criterio_visual","basis":"Interpretación visual del material documental; el acabado, tono y parámetros PBR no son una especificación contractual.","physicalMaterialUnchanged":true} | 0.176 | Hormigón armado · clase pendiente de confirmar | Hormigón armado · gris natural | found_0904_075ddcfd9c66be | Geometría de cimentación del fabricante; no se extrapola HA-30 de la nota de pedestales. | Clase no confirmada en la hoja de equipo | concrete_reinforced | [0.666667,0.662745,0.619608] | 0.96 | Zona de separación de aire; BIM · Cimentaciones | 0.450753 | 0.450754 | 1.1 | 286.1 | 287.2 | F-HV-CONTAINER | ["HV-CONTAINER"] | [] | 14–14 | ["553E/5544","1DB82","1DE55"] | F-HV-CONTAINER/Cimentación y plataforma del módulo HV-CONTAINER · pilar KZ1 06 | foundation | Geometría de fabricante; implantación absoluta provisional | HV-CONTAINER | Cimentaciones de equipos y pedestales del fabricante · revisión recibida 04/09/2026 | 553E/5544, 1DB82, 1DE55 | 0 | 1.1 | 0.16 | Cotas relativas del dibujo. La equivalencia con un datum absoluto está pendiente. | Z del modelo = cota relativa + 1,10 m. Correspondencia provisional con 286,10 m; no es cota de obra confirmada. | Sección y contornos del fabricante; incidencias conservadas | 0.4 | 0.4 | La planta general y algunos croquis de apoyo muestran dimensiones transversales distintas. Se usan el contorno de cimentación y los centros de pilares de la implantación general; sección de viga VC1 400 × 400 mm y vuelo a 1050 mm del eje según detalle. / La capa de mortero sobre la losa no tiene una referencia vertical inequívoca; no se duplica una capa independiente en esa losa.
Cimentación y plataforma del módulo HV-CONTAINER · pilar KZ1 07 | Parcela industrial Jinhong | Cimentación industrial | Cimentaciones de equipos y pedestales del fabricante · revisión recibida 04/09/2026 | 0.450754 | 0.450754 | 1.1 | 2.08 | 0.176 | process_plant | Zona de separación de aire | {"name":"Hormigón armado · clase pendiente de confirmar","status":"Clase no confirmada en la hoja de equipo","source":"Geometría de cimentación del fabricante; no se extrapola HA-30 de la nota de pedestales."} | {"documented":[{"label":"Extensión local X","value":0.4,"unit":"m","source":"553E/5544, 1DB82, 1DE55","status":"derivada del contorno CAD"},{"label":"Extensión local Y","value":0.4,"unit":"m","source":"553E/5544, 1DB82, 1DE55","status":"derivada del contorno CAD"},{"label":"Cota inferior relativa adoptada","value":0,"unit":"m","source":"14–14","status":"interpretación con conflicto conservado"},{"label":"Cota superior relativa adoptada","value":1.1,"unit":"m","source":"14–14","status":"documentada / separación por material"}],"geometry":[{"label":"Extensión de la malla en X","value":0.4507539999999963,"unit":"m","source":"Geometría releída del IFC; datum absoluto de proceso provisional","status":"derivado"},{"label":"Extensión de la malla en Y","value":0.45075400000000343,"unit":"m","source":"Geometría releída del IFC; datum absoluto de proceso provisional","status":"derivado"},{"label":"Extensión de la malla en Z","value":1.1,"unit":"m","source":"Geometría releída del IFC; datum absoluto de proceso provisional","status":"derivado"},{"label":"Cota inferior de visualización","value":286.1,"unit":"m","source":"Geometría releída del IFC; datum absoluto de proceso provisional","status":"derivado"},{"label":"Cota superior de visualización","value":287.2,"unit":"m","source":"Geometría releída del IFC; datum absoluto de proceso provisional","status":"derivado"}]} | {"documentId":"LHD2609-JG00100-20260904","title":"Cimentaciones de equipos y pedestales del fabricante · revisión recibida 04/09/2026","date":"2026-09-04","sheet":"14–14","fileName":"LHD2609-JG00100_20260904.dwg","revisionCaveat":"Fecha de revisión tomada del nombre recibido; cajetines internos mantienen 02/07/2026 y algunos textos de plantilla.","sourceFileSha256":"b42eb027b7bc0b14c38d1d13514f4899b58a732aa8d0ba2ccf10fa2fc3192890"} | provisional | ["La planta general y algunos croquis de apoyo muestran dimensiones transversales distintas. Se usan el contorno de cimentación y los centros de pilares de la implantación general; sección de viga VC1 400 × 400 mm y vuelo a 1050 mm del eje según detalle.","La capa de mortero sobre la losa no tiene una referencia vertical inequívoca; no se duplica una capa independiente en esa losa."] | {"Cota inferior relativa (m)":0,"Cota superior relativa (m)":1.1,"Cero absoluto de visualización (m)":286.1,"Estado del cero absoluto":"Provisional","Criterio":"Las cotas relativas proceden del dibujo; la equivalencia absoluta no está confirmada."} | {"boundingBoxM":{"min":[57.60681,82.711258,1.1],"max":[58.057564,83.162012,2.2]},"extentsM":[0.450754,0.450754,1.1],"meshSurfaceM2":2.08,"meshVolumeM3":0.176,"closedSolid":true,"basis":"Magnitudes de las mallas representadas, no cantidades certificadas de obra, compra o fabricación. Las partes pueden compartir superficies; no se suman como un despiece de materiales."} | {"profileId":"concrete_reinforced","name":"Hormigón armado · gris natural","materialName":"Hormigón armado · clase pendiente de confirmar","physicalMaterialStatus":"Clase no confirmada en la hoja de equipo","physicalMaterialSource":"Geometría de cimentación del fabricante; no se extrapola HA-30 de la nota de pedestales.","appearanceStatus":"criterio_visual","appearanceBasis":"Interpretación visual del material documental; el acabado, tono y parámetros PBR no son una especificación contractual.","note":"La apariencia gráfica no modifica ni confirma la especificación física del material."} | {"elementId":"found_0904_b5531b2caa3049","ifcGuid":"0w5GC9qnLU08QMRbYug0w8","ifcClass":"IfcFooting","buildingId":"process_plant","buildingName":"Zona de separación de aire","sourceDocumentId":"LHD2609-JG00100-20260904","sourceRepresentationKind":"foundation"} | {"layerId":"foundations","layerName":"Cimentaciones","role":"Cimentación industrial","basis":"Clasificación por función del elemento; no modifica las especificaciones documentales."} | {"profileId":"concrete_reinforced","name":"Hormigón armado · gris natural","status":"criterio_visual","basis":"Interpretación visual del material documental; el acabado, tono y parámetros PBR no son una especificación contractual.","physicalMaterialUnchanged":true} | 0.176 | Hormigón armado · clase pendiente de confirmar | Hormigón armado · gris natural | found_0904_b5531b2caa3049 | Geometría de cimentación del fabricante; no se extrapola HA-30 de la nota de pedestales. | Clase no confirmada en la hoja de equipo | concrete_reinforced | [0.666667,0.662745,0.619608] | 0.96 | Zona de separación de aire; BIM · Cimentaciones | 0.450754 | 0.450754 | 1.1 | 286.1 | 287.2 | F-HV-CONTAINER | ["HV-CONTAINER"] | [] | 14–14 | ["553E/5544","1DB82","1DE55"] | F-HV-CONTAINER/Cimentación y plataforma del módulo HV-CONTAINER · pilar KZ1 07 | foundation | Geometría de fabricante; implantación absoluta provisional | HV-CONTAINER | Cimentaciones de equipos y pedestales del fabricante · revisión recibida 04/09/2026 | 553E/5544, 1DB82, 1DE55 | 0 | 1.1 | 0.16 | Cotas relativas del dibujo. La equivalencia con un datum absoluto está pendiente. | Z del modelo = cota relativa + 1,10 m. Correspondencia provisional con 286,10 m; no es cota de obra confirmada. | Sección y contornos del fabricante; incidencias conservadas | 0.4 | 0.4 | La planta general y algunos croquis de apoyo muestran dimensiones transversales distintas. Se usan el contorno de cimentación y los centros de pilares de la implantación general; sección de viga VC1 400 × 400 mm y vuelo a 1050 mm del eje según detalle. / La capa de mortero sobre la losa no tiene una referencia vertical inequívoca; no se duplica una capa independiente en esa losa.
Cimentación y plataforma del módulo HV-CONTAINER · pilar KZ1 08 | Parcela industrial Jinhong | Cimentación industrial | Cimentaciones de equipos y pedestales del fabricante · revisión recibida 04/09/2026 | 0.450754 | 0.450754 | 1.1 | 2.08 | 0.176 | process_plant | Zona de separación de aire | {"name":"Hormigón armado · clase pendiente de confirmar","status":"Clase no confirmada en la hoja de equipo","source":"Geometría de cimentación del fabricante; no se extrapola HA-30 de la nota de pedestales."} | {"documented":[{"label":"Extensión local X","value":0.4,"unit":"m","source":"553E/5544, 1DB82, 1DE55","status":"derivada del contorno CAD"},{"label":"Extensión local Y","value":0.4,"unit":"m","source":"553E/5544, 1DB82, 1DE55","status":"derivada del contorno CAD"},{"label":"Cota inferior relativa adoptada","value":0,"unit":"m","source":"14–14","status":"interpretación con conflicto conservado"},{"label":"Cota superior relativa adoptada","value":1.1,"unit":"m","source":"14–14","status":"documentada / separación por material"}],"geometry":[{"label":"Extensión de la malla en X","value":0.4507539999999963,"unit":"m","source":"Geometría releída del IFC; datum absoluto de proceso provisional","status":"derivado"},{"label":"Extensión de la malla en Y","value":0.45075400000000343,"unit":"m","source":"Geometría releída del IFC; datum absoluto de proceso provisional","status":"derivado"},{"label":"Extensión de la malla en Z","value":1.1,"unit":"m","source":"Geometría releída del IFC; datum absoluto de proceso provisional","status":"derivado"},{"label":"Cota inferior de visualización","value":286.1,"unit":"m","source":"Geometría releída del IFC; datum absoluto de proceso provisional","status":"derivado"},{"label":"Cota superior de visualización","value":287.2,"unit":"m","source":"Geometría releída del IFC; datum absoluto de proceso provisional","status":"derivado"}]} | {"documentId":"LHD2609-JG00100-20260904","title":"Cimentaciones de equipos y pedestales del fabricante · revisión recibida 04/09/2026","date":"2026-09-04","sheet":"14–14","fileName":"LHD2609-JG00100_20260904.dwg","revisionCaveat":"Fecha de revisión tomada del nombre recibido; cajetines internos mantienen 02/07/2026 y algunos textos de plantilla.","sourceFileSha256":"b42eb027b7bc0b14c38d1d13514f4899b58a732aa8d0ba2ccf10fa2fc3192890"} | provisional | ["La planta general y algunos croquis de apoyo muestran dimensiones transversales distintas. Se usan el contorno de cimentación y los centros de pilares de la implantación general; sección de viga VC1 400 × 400 mm y vuelo a 1050 mm del eje según detalle.","La capa de mortero sobre la losa no tiene una referencia vertical inequívoca; no se duplica una capa independiente en esa losa."] | {"Cota inferior relativa (m)":0,"Cota superior relativa (m)":1.1,"Cero absoluto de visualización (m)":286.1,"Estado del cero absoluto":"Provisional","Criterio":"Las cotas relativas proceden del dibujo; la equivalencia absoluta no está confirmada."} | {"boundingBoxM":{"min":[59.897759,82.396286,1.1],"max":[60.348513,82.84704,2.2]},"extentsM":[0.450754,0.450754,1.1],"meshSurfaceM2":2.080001,"meshVolumeM3":0.176,"closedSolid":true,"basis":"Magnitudes de las mallas representadas, no cantidades certificadas de obra, compra o fabricación. Las partes pueden compartir superficies; no se suman como un despiece de materiales."} | {"profileId":"concrete_reinforced","name":"Hormigón armado · gris natural","materialName":"Hormigón armado · clase pendiente de confirmar","physicalMaterialStatus":"Clase no confirmada en la hoja de equipo","physicalMaterialSource":"Geometría de cimentación del fabricante; no se extrapola HA-30 de la nota de pedestales.","appearanceStatus":"criterio_visual","appearanceBasis":"Interpretación visual del material documental; el acabado, tono y parámetros PBR no son una especificación contractual.","note":"La apariencia gráfica no modifica ni confirma la especificación física del material."} | {"elementId":"found_0904_d5c6b9e968cd60","ifcGuid":"23oim3sEjO1f1lBQBbNAAd","ifcClass":"IfcFooting","buildingId":"process_plant","buildingName":"Zona de separación de aire","sourceDocumentId":"LHD2609-JG00100-20260904","sourceRepresentationKind":"foundation"} | {"layerId":"foundations","layerName":"Cimentaciones","role":"Cimentación industrial","basis":"Clasificación por función del elemento; no modifica las especificaciones documentales."} | {"profileId":"concrete_reinforced","name":"Hormigón armado · gris natural","status":"criterio_visual","basis":"Interpretación visual del material documental; el acabado, tono y parámetros PBR no son una especificación contractual.","physicalMaterialUnchanged":true} | 0.176 | Hormigón armado · clase pendiente de confirmar | Hormigón armado · gris natural | found_0904_d5c6b9e968cd60 | Geometría de cimentación del fabricante; no se extrapola HA-30 de la nota de pedestales. | Clase no confirmada en la hoja de equipo | concrete_reinforced | [0.666667,0.662745,0.619608] | 0.96 | Zona de separación de aire; BIM · Cimentaciones | 0.450754 | 0.450754 | 1.1 | 286.1 | 287.2 | F-HV-CONTAINER | ["HV-CONTAINER"] | [] | 14–14 | ["553E/5544","1DB82","1DE55"] | F-HV-CONTAINER/Cimentación y plataforma del módulo HV-CONTAINER · pilar KZ1 08 | foundation | Geometría de fabricante; implantación absoluta provisional | HV-CONTAINER | Cimentaciones de equipos y pedestales del fabricante · revisión recibida 04/09/2026 | 553E/5544, 1DB82, 1DE55 | 0 | 1.1 | 0.16 | Cotas relativas del dibujo. La equivalencia con un datum absoluto está pendiente. | Z del modelo = cota relativa + 1,10 m. Correspondencia provisional con 286,10 m; no es cota de obra confirmada. | Sección y contornos del fabricante; incidencias conservadas | 0.4 | 0.4 | La planta general y algunos croquis de apoyo muestran dimensiones transversales distintas. Se usan el contorno de cimentación y los centros de pilares de la implantación general; sección de viga VC1 400 × 400 mm y vuelo a 1050 mm del eje según detalle. / La capa de mortero sobre la losa no tiene una referencia vertical inequívoca; no se duplica una capa independiente en esa losa.
Cimentación y plataforma del módulo HV-CONTAINER · pilar KZ1 09 | Parcela industrial Jinhong | Cimentación industrial | Cimentaciones de equipos y pedestales del fabricante · revisión recibida 04/09/2026 | 0.450754 | 0.450754 | 1.1 | 2.08 | 0.176 | process_plant | Zona de separación de aire | {"name":"Hormigón armado · clase pendiente de confirmar","status":"Clase no confirmada en la hoja de equipo","source":"Geometría de cimentación del fabricante; no se extrapola HA-30 de la nota de pedestales."} | {"documented":[{"label":"Extensión local X","value":0.4,"unit":"m","source":"553E/5544, 1DB82, 1DE55","status":"derivada del contorno CAD"},{"label":"Extensión local Y","value":0.4,"unit":"m","source":"553E/5544, 1DB82, 1DE55","status":"derivada del contorno CAD"},{"label":"Cota inferior relativa adoptada","value":0,"unit":"m","source":"14–14","status":"interpretación con conflicto conservado"},{"label":"Cota superior relativa adoptada","value":1.1,"unit":"m","source":"14–14","status":"documentada / separación por material"}],"geometry":[{"label":"Extensión de la malla en X","value":0.4507539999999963,"unit":"m","source":"Geometría releída del IFC; datum absoluto de proceso provisional","status":"derivado"},{"label":"Extensión de la malla en Y","value":0.45075400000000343,"unit":"m","source":"Geometría releída del IFC; datum absoluto de proceso provisional","status":"derivado"},{"label":"Extensión de la malla en Z","value":1.1,"unit":"m","source":"Geometría releída del IFC; datum absoluto de proceso provisional","status":"derivado"},{"label":"Cota inferior de visualización","value":286.1,"unit":"m","source":"Geometría releída del IFC; datum absoluto de proceso provisional","status":"derivado"},{"label":"Cota superior de visualización","value":287.2,"unit":"m","source":"Geometría releída del IFC; datum absoluto de proceso provisional","status":"derivado"}]} | {"documentId":"LHD2609-JG00100-20260904","title":"Cimentaciones de equipos y pedestales del fabricante · revisión recibida 04/09/2026","date":"2026-09-04","sheet":"14–14","fileName":"LHD2609-JG00100_20260904.dwg","revisionCaveat":"Fecha de revisión tomada del nombre recibido; cajetines internos mantienen 02/07/2026 y algunos textos de plantilla.","sourceFileSha256":"b42eb027b7bc0b14c38d1d13514f4899b58a732aa8d0ba2ccf10fa2fc3192890"} | provisional | ["La planta general y algunos croquis de apoyo muestran dimensiones transversales distintas. Se usan el contorno de cimentación y los centros de pilares de la implantación general; sección de viga VC1 400 × 400 mm y vuelo a 1050 mm del eje según detalle.","La capa de mortero sobre la losa no tiene una referencia vertical inequívoca; no se duplica una capa independiente en esa losa."] | {"Cota inferior relativa (m)":0,"Cota superior relativa (m)":1.1,"Cero absoluto de visualización (m)":286.1,"Estado del cero absoluto":"Provisional","Criterio":"Las cotas relativas proceden del dibujo; la equivalencia absoluta no está confirmada."} | {"boundingBoxM":{"min":[62.188709,82.081315,1.1],"max":[62.639463,82.532069,2.2]},"extentsM":[0.450754,0.450754,1.1],"meshSurfaceM2":2.080001,"meshVolumeM3":0.176,"closedSolid":true,"basis":"Magnitudes de las mallas representadas, no cantidades certificadas de obra, compra o fabricación. Las partes pueden compartir superficies; no se suman como un despiece de materiales."} | {"profileId":"concrete_reinforced","name":"Hormigón armado · gris natural","materialName":"Hormigón armado · clase pendiente de confirmar","physicalMaterialStatus":"Clase no confirmada en la hoja de equipo","physicalMaterialSource":"Geometría de cimentación del fabricante; no se extrapola HA-30 de la nota de pedestales.","appearanceStatus":"criterio_visual","appearanceBasis":"Interpretación visual del material documental; el acabado, tono y parámetros PBR no son una especificación contractual.","note":"La apariencia gráfica no modifica ni confirma la especificación física del material."} | {"elementId":"found_0904_aa2586cb630803","ifcGuid":"2yEhF5cEPRLQ8QGfG4m2Ym","ifcClass":"IfcFooting","buildingId":"process_plant","buildingName":"Zona de separación de aire","sourceDocumentId":"LHD2609-JG00100-20260904","sourceRepresentationKind":"foundation"} | {"layerId":"foundations","layerName":"Cimentaciones","role":"Cimentación industrial","basis":"Clasificación por función del elemento; no modifica las especificaciones documentales."} | {"profileId":"concrete_reinforced","name":"Hormigón armado · gris natural","status":"criterio_visual","basis":"Interpretación visual del material documental; el acabado, tono y parámetros PBR no son una especificación contractual.","physicalMaterialUnchanged":true} | 0.176 | Hormigón armado · clase pendiente de confirmar | Hormigón armado · gris natural | found_0904_aa2586cb630803 | Geometría de cimentación del fabricante; no se extrapola HA-30 de la nota de pedestales. | Clase no confirmada en la hoja de equipo | concrete_reinforced | [0.666667,0.662745,0.619608] | 0.96 | Zona de separación de aire; BIM · Cimentaciones | 0.450754 | 0.450754 | 1.1 | 286.1 | 287.2 | F-HV-CONTAINER | ["HV-CONTAINER"] | [] | 14–14 | ["553E/5544","1DB82","1DE55"] | F-HV-CONTAINER/Cimentación y plataforma del módulo HV-CONTAINER · pilar KZ1 09 | foundation | Geometría de fabricante; implantación absoluta provisional | HV-CONTAINER | Cimentaciones de equipos y pedestales del fabricante · revisión recibida 04/09/2026 | 553E/5544, 1DB82, 1DE55 | 0 | 1.1 | 0.16 | Cotas relativas del dibujo. La equivalencia con un datum absoluto está pendiente. | Z del modelo = cota relativa + 1,10 m. Correspondencia provisional con 286,10 m; no es cota de obra confirmada. | Sección y contornos del fabricante; incidencias conservadas | 0.4 | 0.4 | La planta general y algunos croquis de apoyo muestran dimensiones transversales distintas. Se usan el contorno de cimentación y los centros de pilares de la implantación general; sección de viga VC1 400 × 400 mm y vuelo a 1050 mm del eje según detalle. / La capa de mortero sobre la losa no tiene una referencia vertical inequívoca; no se duplica una capa independiente en esa losa.
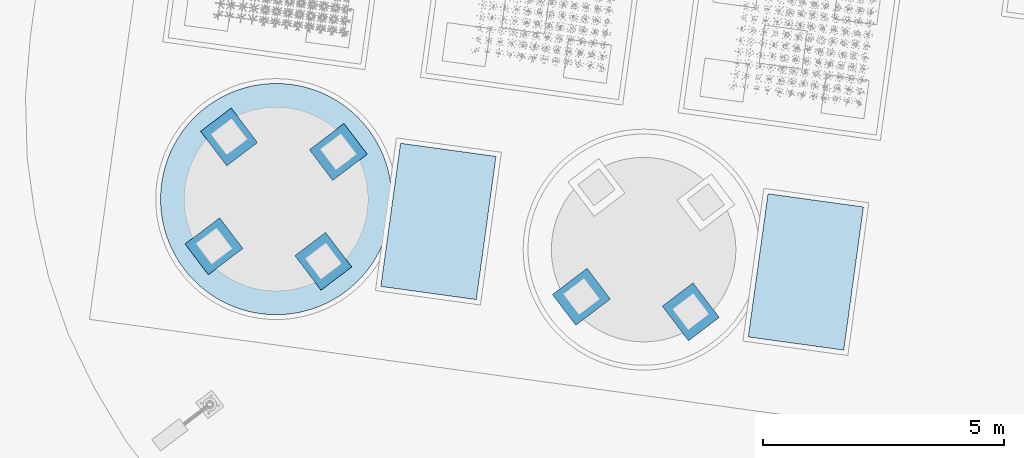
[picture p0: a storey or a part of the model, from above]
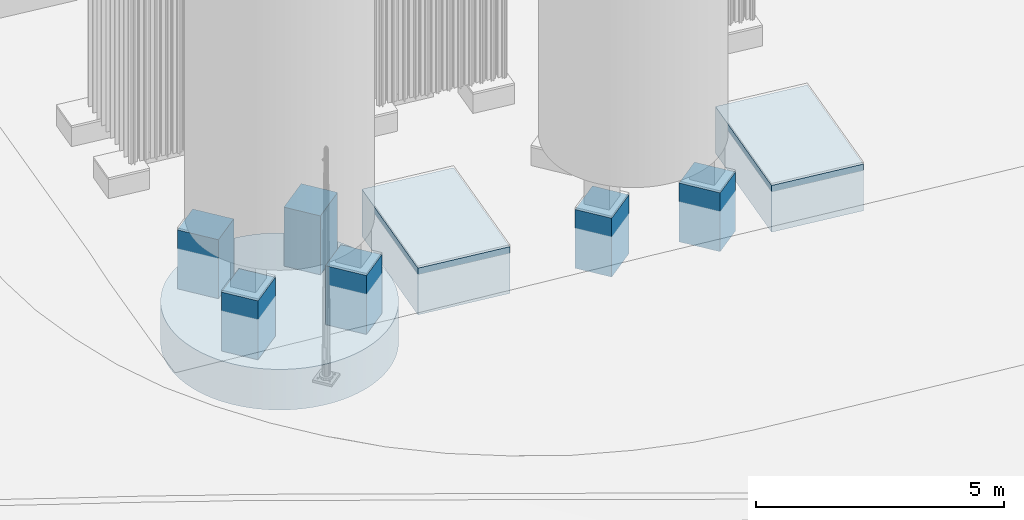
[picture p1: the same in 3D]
Properties of the parts of a building model (IFC4), part 76 of 134

# IfcFooting (214)
Name | In | Description = category = Categoria = Funcion | Document | ExtensionX (m) | ExtensionY (m) | ExtensionZ (m) | SuperficieDeLaMalla (m2) | VolumenGeometrico (m3) | buildingId | buildingName | material | dimensions | JH_InformacionBIM, source = DocumentoFuente | JH_InformacionBIM, status = EstadoDeInformacion | issues = IncidenciasPendientes | positioning = PosicionYEstado | geometryMetrics | materialAppearance | visualizationIdentity | classification | appearance | Volumen geométrico (m³) | JH_Trazabilidad, Material = name | Acabado de visualización = Acabado | Identificador | JH_EvidenciaDeMaterial, source | JH_EvidenciaDeMaterial, status | Perfil | ColorRGB | Rugosidad | Group | Extensión de la malla en X (m) | Extensión de la malla en Y (m) | Extensión de la malla en Z (m) = Espesor o altura real de sección (m) | Cota inferior de visualización (m) | Cota superior de visualización (m) | assemblyId = Conjunto de cimentación | equipmentIds | supportPositionIds | sectionRef = Sección de referencia | sourceCadHandles | stableElementKey | representationKind | geometryStatus | Equipos asociados | Documento de origen | Identificadores CAD de referencia | Cota inferior relativa (m) = Cota inferior relativa adoptada (m) | Cota superior relativa (m) = Cota superior relativa adoptada (m) | Área de planta (m²) | Referencia vertical | Implantación para visualización | Estado de la geometría | Extensión local X (m) | Extensión local Y (m) | Incidencias de origen
Cimentación y plataforma del módulo HV-CONTAINER · pilar KZ1 10 | Parcela industrial Jinhong | Cimentación industrial | Cimentaciones de equipos y pedestales del fabricante · revisión recibida 04/09/2026 | 0.450754 | 0.450754 | 1.1 | 2.08 | 0.176 | process_plant | Zona de separación de aire | {"name":"Hormigón armado · clase pendiente de confirmar","status":"Clase no confirmada en la hoja de equipo","source":"Geometría de cimentación del fabricante; no se extrapola HA-30 de la nota de pedestales."} | {"documented":[{"label":"Extensión local X","value":0.4,"unit":"m","source":"553E/5544, 1DB82, 1DE55","status":"derivada del contorno CAD"},{"label":"Extensión local Y","value":0.4,"unit":"m","source":"553E/5544, 1DB82, 1DE55","status":"derivada del contorno CAD"},{"label":"Cota inferior relativa adoptada","value":0,"unit":"m","source":"14–14","status":"interpretación con conflicto conservado"},{"label":"Cota superior relativa adoptada","value":1.1,"unit":"m","source":"14–14","status":"documentada / separación por material"}],"geometry":[{"label":"Extensión de la malla en X","value":0.45075400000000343,"unit":"m","source":"Geometría releída del IFC; datum absoluto de proceso provisional","status":"derivado"},{"label":"Extensión de la malla en Y","value":0.4507539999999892,"unit":"m","source":"Geometría releída del IFC; datum absoluto de proceso provisional","status":"derivado"},{"label":"Extensión de la malla en Z","value":1.1,"unit":"m","source":"Geometría releída del IFC; datum absoluto de proceso provisional","status":"derivado"},{"label":"Cota inferior de visualización","value":286.1,"unit":"m","source":"Geometría releída del IFC; datum absoluto de proceso provisional","status":"derivado"},{"label":"Cota superior de visualización","value":287.2,"unit":"m","source":"Geometría releída del IFC; datum absoluto de proceso provisional","status":"derivado"}]} | {"documentId":"LHD2609-JG00100-20260904","title":"Cimentaciones de equipos y pedestales del fabricante · revisión recibida 04/09/2026","date":"2026-09-04","sheet":"14–14","fileName":"LHD2609-JG00100_20260904.dwg","revisionCaveat":"Fecha de revisión tomada del nombre recibido; cajetines internos mantienen 02/07/2026 y algunos textos de plantilla.","sourceFileSha256":"b42eb027b7bc0b14c38d1d13514f4899b58a732aa8d0ba2ccf10fa2fc3192890"} | provisional | ["La planta general y algunos croquis de apoyo muestran dimensiones transversales distintas. Se usan el contorno de cimentación y los centros de pilares de la implantación general; sección de viga VC1 400 × 400 mm y vuelo a 1050 mm del eje según detalle.","La capa de mortero sobre la losa no tiene una referencia vertical inequívoca; no se duplica una capa independiente en esa losa."] | {"Cota inferior relativa (m)":0,"Cota superior relativa (m)":1.1,"Cero absoluto de visualización (m)":286.1,"Estado del cero absoluto":"Provisional","Criterio":"Las cotas relativas proceden del dibujo; la equivalencia absoluta no está confirmada."} | {"boundingBoxM":{"min":[64.479658,81.766343,1.1],"max":[64.930412,82.217097,2.2]},"extentsM":[0.450754,0.450754,1.1],"meshSurfaceM2":2.079998,"meshVolumeM3":0.176,"closedSolid":true,"basis":"Magnitudes de las mallas representadas, no cantidades certificadas de obra, compra o fabricación. Las partes pueden compartir superficies; no se suman como un despiece de materiales."} | {"profileId":"concrete_reinforced","name":"Hormigón armado · gris natural","materialName":"Hormigón armado · clase pendiente de confirmar","physicalMaterialStatus":"Clase no confirmada en la hoja de equipo","physicalMaterialSource":"Geometría de cimentación del fabricante; no se extrapola HA-30 de la nota de pedestales.","appearanceStatus":"criterio_visual","appearanceBasis":"Interpretación visual del material documental; el acabado, tono y parámetros PBR no son una especificación contractual.","note":"La apariencia gráfica no modifica ni confirma la especificación física del material."} | {"elementId":"found_0904_5732c355da4910","ifcGuid":"1o3TPj3QvMsBL68ZC3lURP","ifcClass":"IfcFooting","buildingId":"process_plant","buildingName":"Zona de separación de aire","sourceDocumentId":"LHD2609-JG00100-20260904","sourceRepresentationKind":"foundation"} | {"layerId":"foundations","layerName":"Cimentaciones","role":"Cimentación industrial","basis":"Clasificación por función del elemento; no modifica las especificaciones documentales."} | {"profileId":"concrete_reinforced","name":"Hormigón armado · gris natural","status":"criterio_visual","basis":"Interpretación visual del material documental; el acabado, tono y parámetros PBR no son una especificación contractual.","physicalMaterialUnchanged":true} | 0.176 | Hormigón armado · clase pendiente de confirmar | Hormigón armado · gris natural | found_0904_5732c355da4910 | Geometría de cimentación del fabricante; no se extrapola HA-30 de la nota de pedestales. | Clase no confirmada en la hoja de equipo | concrete_reinforced | [0.666667,0.662745,0.619608] | 0.96 | Zona de separación de aire; BIM · Cimentaciones | 0.450754 | 0.450754 | 1.1 | 286.1 | 287.2 | F-HV-CONTAINER | ["HV-CONTAINER"] | [] | 14–14 | ["553E/5544","1DB82","1DE55"] | F-HV-CONTAINER/Cimentación y plataforma del módulo HV-CONTAINER · pilar KZ1 10 | foundation | Geometría de fabricante; implantación absoluta provisional | HV-CONTAINER | Cimentaciones de equipos y pedestales del fabricante · revisión recibida 04/09/2026 | 553E/5544, 1DB82, 1DE55 | 0 | 1.1 | 0.16 | Cotas relativas del dibujo. La equivalencia con un datum absoluto está pendiente. | Z del modelo = cota relativa + 1,10 m. Correspondencia provisional con 286,10 m; no es cota de obra confirmada. | Sección y contornos del fabricante; incidencias conservadas | 0.4 | 0.4 | La planta general y algunos croquis de apoyo muestran dimensiones transversales distintas. Se usan el contorno de cimentación y los centros de pilares de la implantación general; sección de viga VC1 400 × 400 mm y vuelo a 1050 mm del eje según detalle. / La capa de mortero sobre la losa no tiene una referencia vertical inequívoca; no se duplica una capa independiente en esa losa.
Cimentación y plataforma del módulo IC-CONTAINER · cuerpo de hormigón | Parcela industrial Jinhong | Cimentación industrial | Cimentaciones de equipos y pedestales del fabricante · revisión recibida 04/09/2026 | 6.27577 | 13.3038 | 1 | 151.87 | 58.56 | process_plant | Zona de separación de aire | {"name":"Hormigón armado · clase pendiente de confirmar","status":"Clase no confirmada en la hoja de equipo","source":"Geometría de cimentación del fabricante; no se extrapola HA-30 de la nota de pedestales."} | {"documented":[{"label":"Extensión local X","value":4.575,"unit":"m","source":"5645/5652, 1DB82, 1DE55","status":"derivada del contorno CAD"},{"label":"Extensión local Y","value":12.8,"unit":"m","source":"5645/5652, 1DB82, 1DE55","status":"derivada del contorno CAD"},{"label":"Cota inferior relativa adoptada","value":-1,"unit":"m","source":"15–15","status":"interpretación con conflicto conservado"},{"label":"Cota superior relativa adoptada","value":0,"unit":"m","source":"15–15","status":"documentada / separación por material"}],"geometry":[{"label":"Extensión de la malla en X","value":6.275774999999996,"unit":"m","source":"Geometría releída del IFC; datum absoluto de proceso provisional","status":"derivado"},{"label":"Extensión de la malla en Y","value":13.303847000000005,"unit":"m","source":"Geometría releída del IFC; datum absoluto de proceso provisional","status":"derivado"},{"label":"Extensión de la malla en Z","value":1.0,"unit":"m","source":"Geometría releída del IFC; datum absoluto de proceso provisional","status":"derivado"},{"label":"Cota inferior de visualización","value":285.1,"unit":"m","source":"Geometría releída del IFC; datum absoluto de proceso provisional","status":"derivado"},{"label":"Cota superior de visualización","value":286.1,"unit":"m","source":"Geometría releída del IFC; datum absoluto de proceso provisional","status":"derivado"}]} | {"documentId":"LHD2609-JG00100-20260904","title":"Cimentaciones de equipos y pedestales del fabricante · revisión recibida 04/09/2026","date":"2026-09-04","sheet":"15–15","fileName":"LHD2609-JG00100_20260904.dwg","revisionCaveat":"Fecha de revisión tomada del nombre recibido; cajetines internos mantienen 02/07/2026 y algunos textos de plantilla.","sourceFileSha256":"b42eb027b7bc0b14c38d1d13514f4899b58a732aa8d0ba2ccf10fa2fc3192890"} | provisional | ["La planta general y algunos croquis de apoyo muestran dimensiones transversales distintas. Se usan el contorno de cimentación y los centros de pilares de la implantación general; sección de viga VC1 400 × 400 mm y vuelo a 1050 mm del eje según detalle.","La capa de mortero sobre la losa no tiene una referencia vertical inequívoca; no se duplica una capa independiente en esa losa."] | {"Cota inferior relativa (m)":-1,"Cota superior relativa (m)":0,"Cero absoluto de visualización (m)":286.1,"Estado del cero absoluto":"Provisional","Criterio":"Las cotas relativas proceden del dibujo; la equivalencia absoluta no está confirmada."} | {"boundingBoxM":{"min":[36.638184,59.487489,0.1],"max":[42.913959,72.791336,1.1]},"extentsM":[6.275775,13.303847,1.0],"meshSurfaceM2":151.869988,"meshVolumeM3":58.559995,"closedSolid":true,"basis":"Magnitudes de las mallas representadas, no cantidades certificadas de obra, compra o fabricación. Las partes pueden compartir superficies; no se suman como un despiece de materiales."} | {"profileId":"concrete_reinforced","name":"Hormigón armado · gris natural","materialName":"Hormigón armado · clase pendiente de confirmar","physicalMaterialStatus":"Clase no confirmada en la hoja de equipo","physicalMaterialSource":"Geometría de cimentación del fabricante; no se extrapola HA-30 de la nota de pedestales.","appearanceStatus":"criterio_visual","appearanceBasis":"Interpretación visual del material documental; el acabado, tono y parámetros PBR no son una especificación contractual.","note":"La apariencia gráfica no modifica ni confirma la especificación física del material."} | {"elementId":"found_0904_b71752b17c94a5","ifcGuid":"1oxSQnTx1Pbxf6tfoKgFDZ","ifcClass":"IfcFooting","buildingId":"process_plant","buildingName":"Zona de separación de aire","sourceDocumentId":"LHD2609-JG00100-20260904","sourceRepresentationKind":"foundation"} | {"layerId":"foundations","layerName":"Cimentaciones","role":"Cimentación industrial","basis":"Clasificación por función del elemento; no modifica las especificaciones documentales."} | {"profileId":"concrete_reinforced","name":"Hormigón armado · gris natural","status":"criterio_visual","basis":"Interpretación visual del material documental; el acabado, tono y parámetros PBR no son una especificación contractual.","physicalMaterialUnchanged":true} | 58.56 | Hormigón armado · clase pendiente de confirmar | Hormigón armado · gris natural | found_0904_b71752b17c94a5 | Geometría de cimentación del fabricante; no se extrapola HA-30 de la nota de pedestales. | Clase no confirmada en la hoja de equipo | concrete_reinforced | [0.666667,0.662745,0.619608] | 0.96 | Zona de separación de aire; BIM · Cimentaciones | 6.27577 | 13.3038 | 1 | 285.1 | 286.1 | F-IC-CONTAINER | ["IC-CONTAINER"] | [] | 15–15 | ["5645/5652","1DB82","1DE55"] | F-IC-CONTAINER/Cimentación y plataforma del módulo IC-CONTAINER · cuerpo de hormigón | foundation | Geometría de fabricante; implantación absoluta provisional | IC-CONTAINER | Cimentaciones de equipos y pedestales del fabricante · revisión recibida 04/09/2026 | 5645/5652, 1DB82, 1DE55 | -1 | 0 | 58.56 | Cotas relativas del dibujo. La equivalencia con un datum absoluto está pendiente. | Z del modelo = cota relativa + 1,10 m. Correspondencia provisional con 286,10 m; no es cota de obra confirmada. | Sección y contornos del fabricante; incidencias conservadas | 4.575 | 12.8 | La planta general y algunos croquis de apoyo muestran dimensiones transversales distintas. Se usan el contorno de cimentación y los centros de pilares de la implantación general; sección de viga VC1 400 × 400 mm y vuelo a 1050 mm del eje según detalle. / La capa de mortero sobre la losa no tiene una referencia vertical inequívoca; no se duplica una capa independiente en esa losa.
Cimentación y plataforma del módulo IC-CONTAINER · pilar KZ1 01 | Parcela industrial Jinhong | Cimentación industrial | Cimentaciones de equipos y pedestales del fabricante · revisión recibida 04/09/2026 | 0.450754 | 0.450754 | 1.1 | 2.08 | 0.176 | process_plant | Zona de separación de aire | {"name":"Hormigón armado · clase pendiente de confirmar","status":"Clase no confirmada en la hoja de equipo","source":"Geometría de cimentación del fabricante; no se extrapola HA-30 de la nota de pedestales."} | {"documented":[{"label":"Extensión local X","value":0.4,"unit":"m","source":"5645/5652, 1DB82, 1DE55","status":"derivada del contorno CAD"},{"label":"Extensión local Y","value":0.4,"unit":"m","source":"5645/5652, 1DB82, 1DE55","status":"derivada del contorno CAD"},{"label":"Cota inferior relativa adoptada","value":0,"unit":"m","source":"15–15","status":"interpretación con conflicto conservado"},{"label":"Cota superior relativa adoptada","value":1.1,"unit":"m","source":"15–15","status":"documentada / separación por material"}],"geometry":[{"label":"Extensión de la malla en X","value":0.4507539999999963,"unit":"m","source":"Geometría releída del IFC; datum absoluto de proceso provisional","status":"derivado"},{"label":"Extensión de la malla en Y","value":0.45075400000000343,"unit":"m","source":"Geometría releída del IFC; datum absoluto de proceso provisional","status":"derivado"},{"label":"Extensión de la malla en Z","value":1.1,"unit":"m","source":"Geometría releída del IFC; datum absoluto de proceso provisional","status":"derivado"},{"label":"Cota inferior de visualización","value":286.1,"unit":"m","source":"Geometría releída del IFC; datum absoluto de proceso provisional","status":"derivado"},{"label":"Cota superior de visualización","value":287.2,"unit":"m","source":"Geometría releída del IFC; datum absoluto de proceso provisional","status":"derivado"}]} | {"documentId":"LHD2609-JG00100-20260904","title":"Cimentaciones de equipos y pedestales del fabricante · revisión recibida 04/09/2026","date":"2026-09-04","sheet":"15–15","fileName":"LHD2609-JG00100_20260904.dwg","revisionCaveat":"Fecha de revisión tomada del nombre recibido; cajetines internos mantienen 02/07/2026 y algunos textos de plantilla.","sourceFileSha256":"b42eb027b7bc0b14c38d1d13514f4899b58a732aa8d0ba2ccf10fa2fc3192890"} | provisional | ["La planta general y algunos croquis de apoyo muestran dimensiones transversales distintas. Se usan el contorno de cimentación y los centros de pilares de la implantación general; sección de viga VC1 400 × 400 mm y vuelo a 1050 mm del eje según detalle.","La capa de mortero sobre la losa no tiene una referencia vertical inequívoca; no se duplica una capa independiente en esa losa."] | {"Cota inferior relativa (m)":0,"Cota superior relativa (m)":1.1,"Cero absoluto de visualización (m)":286.1,"Estado del cero absoluto":"Provisional","Criterio":"Las cotas relativas proceden del dibujo; la equivalencia absoluta no está confirmada."} | {"boundingBoxM":{"min":[40.76991,61.658313,1.1],"max":[41.220664,62.109067,2.2]},"extentsM":[0.450754,0.450754,1.1],"meshSurfaceM2":2.080001,"meshVolumeM3":0.176,"closedSolid":true,"basis":"Magnitudes de las mallas representadas, no cantidades certificadas de obra, compra o fabricación. Las partes pueden compartir superficies; no se suman como un despiece de materiales."} | {"profileId":"concrete_reinforced","name":"Hormigón armado · gris natural","materialName":"Hormigón armado · clase pendiente de confirmar","physicalMaterialStatus":"Clase no confirmada en la hoja de equipo","physicalMaterialSource":"Geometría de cimentación del fabricante; no se extrapola HA-30 de la nota de pedestales.","appearanceStatus":"criterio_visual","appearanceBasis":"Interpretación visual del material documental; el acabado, tono y parámetros PBR no son una especificación contractual.","note":"La apariencia gráfica no modifica ni confirma la especificación física del material."} | {"elementId":"found_0904_29a4127fe30ab6","ifcGuid":"2mtbRrlyzKMfPGHqpDYyC7","ifcClass":"IfcFooting","buildingId":"process_plant","buildingName":"Zona de separación de aire","sourceDocumentId":"LHD2609-JG00100-20260904","sourceRepresentationKind":"foundation"} | {"layerId":"foundations","layerName":"Cimentaciones","role":"Cimentación industrial","basis":"Clasificación por función del elemento; no modifica las especificaciones documentales."} | {"profileId":"concrete_reinforced","name":"Hormigón armado · gris natural","status":"criterio_visual","basis":"Interpretación visual del material documental; el acabado, tono y parámetros PBR no son una especificación contractual.","physicalMaterialUnchanged":true} | 0.176 | Hormigón armado · clase pendiente de confirmar | Hormigón armado · gris natural | found_0904_29a4127fe30ab6 | Geometría de cimentación del fabricante; no se extrapola HA-30 de la nota de pedestales. | Clase no confirmada en la hoja de equipo | concrete_reinforced | [0.666667,0.662745,0.619608] | 0.96 | Zona de separación de aire; BIM · Cimentaciones | 0.450754 | 0.450754 | 1.1 | 286.1 | 287.2 | F-IC-CONTAINER | ["IC-CONTAINER"] | [] | 15–15 | ["5645/5652","1DB82","1DE55"] | F-IC-CONTAINER/Cimentación y plataforma del módulo IC-CONTAINER · pilar KZ1 01 | foundation | Geometría de fabricante; implantación absoluta provisional | IC-CONTAINER | Cimentaciones de equipos y pedestales del fabricante · revisión recibida 04/09/2026 | 5645/5652, 1DB82, 1DE55 | 0 | 1.1 | 0.16 | Cotas relativas del dibujo. La equivalencia con un datum absoluto está pendiente. | Z del modelo = cota relativa + 1,10 m. Correspondencia provisional con 286,10 m; no es cota de obra confirmada. | Sección y contornos del fabricante; incidencias conservadas | 0.4 | 0.4 | La planta general y algunos croquis de apoyo muestran dimensiones transversales distintas. Se usan el contorno de cimentación y los centros de pilares de la implantación general; sección de viga VC1 400 × 400 mm y vuelo a 1050 mm del eje según detalle. / La capa de mortero sobre la losa no tiene una referencia vertical inequívoca; no se duplica una capa independiente en esa losa.
Cimentación y plataforma del módulo IC-CONTAINER · pilar KZ1 02 | Parcela industrial Jinhong | Cimentación industrial | Cimentaciones de equipos y pedestales del fabricante · revisión recibida 04/09/2026 | 0.450754 | 0.450754 | 1.1 | 2.08 | 0.176 | process_plant | Zona de separación de aire | {"name":"Hormigón armado · clase pendiente de confirmar","status":"Clase no confirmada en la hoja de equipo","source":"Geometría de cimentación del fabricante; no se extrapola HA-30 de la nota de pedestales."} | {"documented":[{"label":"Extensión local X","value":0.4,"unit":"m","source":"5645/5652, 1DB82, 1DE55","status":"derivada del contorno CAD"},{"label":"Extensión local Y","value":0.4,"unit":"m","source":"5645/5652, 1DB82, 1DE55","status":"derivada del contorno CAD"},{"label":"Cota inferior relativa adoptada","value":0,"unit":"m","source":"15–15","status":"interpretación con conflicto conservado"},{"label":"Cota superior relativa adoptada","value":1.1,"unit":"m","source":"15–15","status":"documentada / separación por material"}],"geometry":[{"label":"Extensión de la malla en X","value":0.45075400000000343,"unit":"m","source":"Geometría releída del IFC; datum absoluto de proceso provisional","status":"derivado"},{"label":"Extensión de la malla en Y","value":0.45075400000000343,"unit":"m","source":"Geometría releída del IFC; datum absoluto de proceso provisional","status":"derivado"},{"label":"Extensión de la malla en Z","value":1.1,"unit":"m","source":"Geometría releída del IFC; datum absoluto de proceso provisional","status":"derivado"},{"label":"Cota inferior de visualización","value":286.1,"unit":"m","source":"Geometría releída del IFC; datum absoluto de proceso provisional","status":"derivado"},{"label":"Cota superior de visualización","value":287.2,"unit":"m","source":"Geometría releída del IFC; datum absoluto de proceso provisional","status":"derivado"}]} | {"documentId":"LHD2609-JG00100-20260904","title":"Cimentaciones de equipos y pedestales del fabricante · revisión recibida 04/09/2026","date":"2026-09-04","sheet":"15–15","fileName":"LHD2609-JG00100_20260904.dwg","revisionCaveat":"Fecha de revisión tomada del nombre recibido; cajetines internos mantienen 02/07/2026 y algunos textos de plantilla.","sourceFileSha256":"b42eb027b7bc0b14c38d1d13514f4899b58a732aa8d0ba2ccf10fa2fc3192890"} | provisional | ["La planta general y algunos croquis de apoyo muestran dimensiones transversales distintas. Se usan el contorno de cimentación y los centros de pilares de la implantación general; sección de viga VC1 400 × 400 mm y vuelo a 1050 mm del eje según detalle.","La capa de mortero sobre la losa no tiene una referencia vertical inequívoca; no se duplica una capa independiente en esa losa."] | {"Cota inferior relativa (m)":0,"Cota superior relativa (m)":1.1,"Cero absoluto de visualización (m)":286.1,"Estado del cero absoluto":"Provisional","Criterio":"Las cotas relativas proceden del dibujo; la equivalencia absoluta no está confirmada."} | {"boundingBoxM":{"min":[41.108717,64.122632,1.1],"max":[41.559471,64.573386,2.2]},"extentsM":[0.450754,0.450754,1.1],"meshSurfaceM2":2.08,"meshVolumeM3":0.176,"closedSolid":true,"basis":"Magnitudes de las mallas representadas, no cantidades certificadas de obra, compra o fabricación. Las partes pueden compartir superficies; no se suman como un despiece de materiales."} | {"profileId":"concrete_reinforced","name":"Hormigón armado · gris natural","materialName":"Hormigón armado · clase pendiente de confirmar","physicalMaterialStatus":"Clase no confirmada en la hoja de equipo","physicalMaterialSource":"Geometría de cimentación del fabricante; no se extrapola HA-30 de la nota de pedestales.","appearanceStatus":"criterio_visual","appearanceBasis":"Interpretación visual del material documental; el acabado, tono y parámetros PBR no son una especificación contractual.","note":"La apariencia gráfica no modifica ni confirma la especificación física del material."} | {"elementId":"found_0904_ddeb8c03984179","ifcGuid":"1IJI3Ex7LKcxwXuisHtVKc","ifcClass":"IfcFooting","buildingId":"process_plant","buildingName":"Zona de separación de aire","sourceDocumentId":"LHD2609-JG00100-20260904","sourceRepresentationKind":"foundation"} | {"layerId":"foundations","layerName":"Cimentaciones","role":"Cimentación industrial","basis":"Clasificación por función del elemento; no modifica las especificaciones documentales."} | {"profileId":"concrete_reinforced","name":"Hormigón armado · gris natural","status":"criterio_visual","basis":"Interpretación visual del material documental; el acabado, tono y parámetros PBR no son una especificación contractual.","physicalMaterialUnchanged":true} | 0.176 | Hormigón armado · clase pendiente de confirmar | Hormigón armado · gris natural | found_0904_ddeb8c03984179 | Geometría de cimentación del fabricante; no se extrapola HA-30 de la nota de pedestales. | Clase no confirmada en la hoja de equipo | concrete_reinforced | [0.666667,0.662745,0.619608] | 0.96 | Zona de separación de aire; BIM · Cimentaciones | 0.450754 | 0.450754 | 1.1 | 286.1 | 287.2 | F-IC-CONTAINER | ["IC-CONTAINER"] | [] | 15–15 | ["5645/5652","1DB82","1DE55"] | F-IC-CONTAINER/Cimentación y plataforma del módulo IC-CONTAINER · pilar KZ1 02 | foundation | Geometría de fabricante; implantación absoluta provisional | IC-CONTAINER | Cimentaciones de equipos y pedestales del fabricante · revisión recibida 04/09/2026 | 5645/5652, 1DB82, 1DE55 | 0 | 1.1 | 0.16 | Cotas relativas del dibujo. La equivalencia con un datum absoluto está pendiente. | Z del modelo = cota relativa + 1,10 m. Correspondencia provisional con 286,10 m; no es cota de obra confirmada. | Sección y contornos del fabricante; incidencias conservadas | 0.4 | 0.4 | La planta general y algunos croquis de apoyo muestran dimensiones transversales distintas. Se usan el contorno de cimentación y los centros de pilares de la implantación general; sección de viga VC1 400 × 400 mm y vuelo a 1050 mm del eje según detalle. / La capa de mortero sobre la losa no tiene una referencia vertical inequívoca; no se duplica una capa independiente en esa losa.
Cimentación y plataforma del módulo IC-CONTAINER · pilar KZ1 03 | Parcela industrial Jinhong | Cimentación industrial | Cimentaciones de equipos y pedestales del fabricante · revisión recibida 04/09/2026 | 0.450754 | 0.450753 | 1.1 | 2.08 | 0.176 | process_plant | Zona de separación de aire | {"name":"Hormigón armado · clase pendiente de confirmar","status":"Clase no confirmada en la hoja de equipo","source":"Geometría de cimentación del fabricante; no se extrapola HA-30 de la nota de pedestales."} | {"documented":[{"label":"Extensión local X","value":0.4,"unit":"m","source":"5645/5652, 1DB82, 1DE55","status":"derivada del contorno CAD"},{"label":"Extensión local Y","value":0.4,"unit":"m","source":"5645/5652, 1DB82, 1DE55","status":"derivada del contorno CAD"},{"label":"Cota inferior relativa adoptada","value":0,"unit":"m","source":"15–15","status":"interpretación con conflicto conservado"},{"label":"Cota superior relativa adoptada","value":1.1,"unit":"m","source":"15–15","status":"documentada / separación por material"}],"geometry":[{"label":"Extensión de la malla en X","value":0.45075400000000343,"unit":"m","source":"Geometría releída del IFC; datum absoluto de proceso provisional","status":"derivado"},{"label":"Extensión de la malla en Y","value":0.45075300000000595,"unit":"m","source":"Geometría releída del IFC; datum absoluto de proceso provisional","status":"derivado"},{"label":"Extensión de la malla en Z","value":1.1,"unit":"m","source":"Geometría releída del IFC; datum absoluto de proceso provisional","status":"derivado"},{"label":"Cota inferior de visualización","value":286.1,"unit":"m","source":"Geometría releída del IFC; datum absoluto de proceso provisional","status":"derivado"},{"label":"Cota superior de visualización","value":287.2,"unit":"m","source":"Geometría releída del IFC; datum absoluto de proceso provisional","status":"derivado"}]} | {"documentId":"LHD2609-JG00100-20260904","title":"Cimentaciones de equipos y pedestales del fabricante · revisión recibida 04/09/2026","date":"2026-09-04","sheet":"15–15","fileName":"LHD2609-JG00100_20260904.dwg","revisionCaveat":"Fecha de revisión tomada del nombre recibido; cajetines internos mantienen 02/07/2026 y algunos textos de plantilla.","sourceFileSha256":"b42eb027b7bc0b14c38d1d13514f4899b58a732aa8d0ba2ccf10fa2fc3192890"} | provisional | ["La planta general y algunos croquis de apoyo muestran dimensiones transversales distintas. Se usan el contorno de cimentación y los centros de pilares de la implantación general; sección de viga VC1 400 × 400 mm y vuelo a 1050 mm del eje según detalle.","La capa de mortero sobre la losa no tiene una referencia vertical inequívoca; no se duplica una capa independiente en esa losa."] | {"Cota inferior relativa (m)":0,"Cota superior relativa (m)":1.1,"Cero absoluto de visualización (m)":286.1,"Estado del cero absoluto":"Provisional","Criterio":"Las cotas relativas proceden del dibujo; la equivalencia absoluta no está confirmada."} | {"boundingBoxM":{"min":[41.447525,66.586951,1.1],"max":[41.898279,67.037704,2.2]},"extentsM":[0.450754,0.450753,1.1],"meshSurfaceM2":2.079999,"meshVolumeM3":0.176,"closedSolid":true,"basis":"Magnitudes de las mallas representadas, no cantidades certificadas de obra, compra o fabricación. Las partes pueden compartir superficies; no se suman como un despiece de materiales."} | {"profileId":"concrete_reinforced","name":"Hormigón armado · gris natural","materialName":"Hormigón armado · clase pendiente de confirmar","physicalMaterialStatus":"Clase no confirmada en la hoja de equipo","physicalMaterialSource":"Geometría de cimentación del fabricante; no se extrapola HA-30 de la nota de pedestales.","appearanceStatus":"criterio_visual","appearanceBasis":"Interpretación visual del material documental; el acabado, tono y parámetros PBR no son una especificación contractual.","note":"La apariencia gráfica no modifica ni confirma la especificación física del material."} | {"elementId":"found_0904_45dfd7825aea35","ifcGuid":"1h6gafh_jTYglmhr1g1cHI","ifcClass":"IfcFooting","buildingId":"process_plant","buildingName":"Zona de separación de aire","sourceDocumentId":"LHD2609-JG00100-20260904","sourceRepresentationKind":"foundation"} | {"layerId":"foundations","layerName":"Cimentaciones","role":"Cimentación industrial","basis":"Clasificación por función del elemento; no modifica las especificaciones documentales."} | {"profileId":"concrete_reinforced","name":"Hormigón armado · gris natural","status":"criterio_visual","basis":"Interpretación visual del material documental; el acabado, tono y parámetros PBR no son una especificación contractual.","physicalMaterialUnchanged":true} | 0.176 | Hormigón armado · clase pendiente de confirmar | Hormigón armado · gris natural | found_0904_45dfd7825aea35 | Geometría de cimentación del fabricante; no se extrapola HA-30 de la nota de pedestales. | Clase no confirmada en la hoja de equipo | concrete_reinforced | [0.666667,0.662745,0.619608] | 0.96 | Zona de separación de aire; BIM · Cimentaciones | 0.450754 | 0.450753 | 1.1 | 286.1 | 287.2 | F-IC-CONTAINER | ["IC-CONTAINER"] | [] | 15–15 | ["5645/5652","1DB82","1DE55"] | F-IC-CONTAINER/Cimentación y plataforma del módulo IC-CONTAINER · pilar KZ1 03 | foundation | Geometría de fabricante; implantación absoluta provisional | IC-CONTAINER | Cimentaciones de equipos y pedestales del fabricante · revisión recibida 04/09/2026 | 5645/5652, 1DB82, 1DE55 | 0 | 1.1 | 0.16 | Cotas relativas del dibujo. La equivalencia con un datum absoluto está pendiente. | Z del modelo = cota relativa + 1,10 m. Correspondencia provisional con 286,10 m; no es cota de obra confirmada. | Sección y contornos del fabricante; incidencias conservadas | 0.4 | 0.4 | La planta general y algunos croquis de apoyo muestran dimensiones transversales distintas. Se usan el contorno de cimentación y los centros de pilares de la implantación general; sección de viga VC1 400 × 400 mm y vuelo a 1050 mm del eje según detalle. / La capa de mortero sobre la losa no tiene una referencia vertical inequívoca; no se duplica una capa independiente en esa losa.
Cimentación y plataforma del módulo IC-CONTAINER · pilar KZ1 04 | Parcela industrial Jinhong | Cimentación industrial | Cimentaciones de equipos y pedestales del fabricante · revisión recibida 04/09/2026 | 0.450754 | 0.450754 | 1.1 | 2.08 | 0.176 | process_plant | Zona de separación de aire | {"name":"Hormigón armado · clase pendiente de confirmar","status":"Clase no confirmada en la hoja de equipo","source":"Geometría de cimentación del fabricante; no se extrapola HA-30 de la nota de pedestales."} | {"documented":[{"label":"Extensión local X","value":0.4,"unit":"m","source":"5645/5652, 1DB82, 1DE55","status":"derivada del contorno CAD"},{"label":"Extensión local Y","value":0.4,"unit":"m","source":"5645/5652, 1DB82, 1DE55","status":"derivada del contorno CAD"},{"label":"Cota inferior relativa adoptada","value":0,"unit":"m","source":"15–15","status":"interpretación con conflicto conservado"},{"label":"Cota superior relativa adoptada","value":1.1,"unit":"m","source":"15–15","status":"documentada / separación por material"}],"geometry":[{"label":"Extensión de la malla en X","value":0.4507539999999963,"unit":"m","source":"Geometría releída del IFC; datum absoluto de proceso provisional","status":"derivado"},{"label":"Extensión de la malla en Y","value":0.4507539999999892,"unit":"m","source":"Geometría releída del IFC; datum absoluto de proceso provisional","status":"derivado"},{"label":"Extensión de la malla en Z","value":1.1,"unit":"m","source":"Geometría releída del IFC; datum absoluto de proceso provisional","status":"derivado"},{"label":"Cota inferior de visualización","value":286.1,"unit":"m","source":"Geometría releída del IFC; datum absoluto de proceso provisional","status":"derivado"},{"label":"Cota superior de visualización","value":287.2,"unit":"m","source":"Geometría releída del IFC; datum absoluto de proceso provisional","status":"derivado"}]} | {"documentId":"LHD2609-JG00100-20260904","title":"Cimentaciones de equipos y pedestales del fabricante · revisión recibida 04/09/2026","date":"2026-09-04","sheet":"15–15","fileName":"LHD2609-JG00100_20260904.dwg","revisionCaveat":"Fecha de revisión tomada del nombre recibido; cajetines internos mantienen 02/07/2026 y algunos textos de plantilla.","sourceFileSha256":"b42eb027b7bc0b14c38d1d13514f4899b58a732aa8d0ba2ccf10fa2fc3192890"} | provisional | ["La planta general y algunos croquis de apoyo muestran dimensiones transversales distintas. Se usan el contorno de cimentación y los centros de pilares de la implantación general; sección de viga VC1 400 × 400 mm y vuelo a 1050 mm del eje según detalle.","La capa de mortero sobre la losa no tiene una referencia vertical inequívoca; no se duplica una capa independiente en esa losa."] | {"Cota inferior relativa (m)":0,"Cota superior relativa (m)":1.1,"Cero absoluto de visualización (m)":286.1,"Estado del cero absoluto":"Provisional","Criterio":"Las cotas relativas proceden del dibujo; la equivalencia absoluta no está confirmada."} | {"boundingBoxM":{"min":[41.786332,69.051269,1.1],"max":[42.237086,69.502023,2.2]},"extentsM":[0.450754,0.450754,1.1],"meshSurfaceM2":2.079998,"meshVolumeM3":0.176,"closedSolid":true,"basis":"Magnitudes de las mallas representadas, no cantidades certificadas de obra, compra o fabricación. Las partes pueden compartir superficies; no se suman como un despiece de materiales."} | {"profileId":"concrete_reinforced","name":"Hormigón armado · gris natural","materialName":"Hormigón armado · clase pendiente de confirmar","physicalMaterialStatus":"Clase no confirmada en la hoja de equipo","physicalMaterialSource":"Geometría de cimentación del fabricante; no se extrapola HA-30 de la nota de pedestales.","appearanceStatus":"criterio_visual","appearanceBasis":"Interpretación visual del material documental; el acabado, tono y parámetros PBR no son una especificación contractual.","note":"La apariencia gráfica no modifica ni confirma la especificación física del material."} | {"elementId":"found_0904_22501c5a816ffd","ifcGuid":"2N_cGVxlDGWuewbNu0OXG2","ifcClass":"IfcFooting","buildingId":"process_plant","buildingName":"Zona de separación de aire","sourceDocumentId":"LHD2609-JG00100-20260904","sourceRepresentationKind":"foundation"} | {"layerId":"foundations","layerName":"Cimentaciones","role":"Cimentación industrial","basis":"Clasificación por función del elemento; no modifica las especificaciones documentales."} | {"profileId":"concrete_reinforced","name":"Hormigón armado · gris natural","status":"criterio_visual","basis":"Interpretación visual del material documental; el acabado, tono y parámetros PBR no son una especificación contractual.","physicalMaterialUnchanged":true} | 0.176 | Hormigón armado · clase pendiente de confirmar | Hormigón armado · gris natural | found_0904_22501c5a816ffd | Geometría de cimentación del fabricante; no se extrapola HA-30 de la nota de pedestales. | Clase no confirmada en la hoja de equipo | concrete_reinforced | [0.666667,0.662745,0.619608] | 0.96 | Zona de separación de aire; BIM · Cimentaciones | 0.450754 | 0.450754 | 1.1 | 286.1 | 287.2 | F-IC-CONTAINER | ["IC-CONTAINER"] | [] | 15–15 | ["5645/5652","1DB82","1DE55"] | F-IC-CONTAINER/Cimentación y plataforma del módulo IC-CONTAINER · pilar KZ1 04 | foundation | Geometría de fabricante; implantación absoluta provisional | IC-CONTAINER | Cimentaciones de equipos y pedestales del fabricante · revisión recibida 04/09/2026 | 5645/5652, 1DB82, 1DE55 | 0 | 1.1 | 0.16 | Cotas relativas del dibujo. La equivalencia con un datum absoluto está pendiente. | Z del modelo = cota relativa + 1,10 m. Correspondencia provisional con 286,10 m; no es cota de obra confirmada. | Sección y contornos del fabricante; incidencias conservadas | 0.4 | 0.4 | La planta general y algunos croquis de apoyo muestran dimensiones transversales distintas. Se usan el contorno de cimentación y los centros de pilares de la implantación general; sección de viga VC1 400 × 400 mm y vuelo a 1050 mm del eje según detalle. / La capa de mortero sobre la losa no tiene una referencia vertical inequívoca; no se duplica una capa independiente en esa losa.
Cimentación y plataforma del módulo IC-CONTAINER · pilar KZ1 05 | Parcela industrial Jinhong | Cimentación industrial | Cimentaciones de equipos y pedestales del fabricante · revisión recibida 04/09/2026 | 0.450754 | 0.450754 | 1.1 | 2.08 | 0.176 | process_plant | Zona de separación de aire | {"name":"Hormigón armado · clase pendiente de confirmar","status":"Clase no confirmada en la hoja de equipo","source":"Geometría de cimentación del fabricante; no se extrapola HA-30 de la nota de pedestales."} | {"documented":[{"label":"Extensión local X","value":0.4,"unit":"m","source":"5645/5652, 1DB82, 1DE55","status":"derivada del contorno CAD"},{"label":"Extensión local Y","value":0.4,"unit":"m","source":"5645/5652, 1DB82, 1DE55","status":"derivada del contorno CAD"},{"label":"Cota inferior relativa adoptada","value":0,"unit":"m","source":"15–15","status":"interpretación con conflicto conservado"},{"label":"Cota superior relativa adoptada","value":1.1,"unit":"m","source":"15–15","status":"documentada / separación por material"}],"geometry":[{"label":"Extensión de la malla en X","value":0.45075400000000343,"unit":"m","source":"Geometría releída del IFC; datum absoluto de proceso provisional","status":"derivado"},{"label":"Extensión de la malla en Y","value":0.45075400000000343,"unit":"m","source":"Geometría releída del IFC; datum absoluto de proceso provisional","status":"derivado"},{"label":"Extensión de la malla en Z","value":1.1,"unit":"m","source":"Geometría releída del IFC; datum absoluto de proceso provisional","status":"derivado"},{"label":"Cota inferior de visualización","value":286.1,"unit":"m","source":"Geometría releída del IFC; datum absoluto de proceso provisional","status":"derivado"},{"label":"Cota superior de visualización","value":287.2,"unit":"m","source":"Geometría releída del IFC; datum absoluto de proceso provisional","status":"derivado"}]} | {"documentId":"LHD2609-JG00100-20260904","title":"Cimentaciones de equipos y pedestales del fabricante · revisión recibida 04/09/2026","date":"2026-09-04","sheet":"15–15","fileName":"LHD2609-JG00100_20260904.dwg","revisionCaveat":"Fecha de revisión tomada del nombre recibido; cajetines internos mantienen 02/07/2026 y algunos textos de plantilla.","sourceFileSha256":"b42eb027b7bc0b14c38d1d13514f4899b58a732aa8d0ba2ccf10fa2fc3192890"} | provisional | ["La planta general y algunos croquis de apoyo muestran dimensiones transversales distintas. Se usan el contorno de cimentación y los centros de pilares de la implantación general; sección de viga VC1 400 × 400 mm y vuelo a 1050 mm del eje según detalle.","La capa de mortero sobre la losa no tiene una referencia vertical inequívoca; no se duplica una capa independiente en esa losa."] | {"Cota inferior relativa (m)":0,"Cota superior relativa (m)":1.1,"Cero absoluto de visualización (m)":286.1,"Estado del cero absoluto":"Provisional","Criterio":"Las cotas relativas proceden del dibujo; la equivalencia absoluta no está confirmada."} | {"boundingBoxM":{"min":[42.125139,71.515588,1.1],"max":[42.575893,71.966342,2.2]},"extentsM":[0.450754,0.450754,1.1],"meshSurfaceM2":2.080001,"meshVolumeM3":0.176,"closedSolid":true,"basis":"Magnitudes de las mallas representadas, no cantidades certificadas de obra, compra o fabricación. Las partes pueden compartir superficies; no se suman como un despiece de materiales."} | {"profileId":"concrete_reinforced","name":"Hormigón armado · gris natural","materialName":"Hormigón armado · clase pendiente de confirmar","physicalMaterialStatus":"Clase no confirmada en la hoja de equipo","physicalMaterialSource":"Geometría de cimentación del fabricante; no se extrapola HA-30 de la nota de pedestales.","appearanceStatus":"criterio_visual","appearanceBasis":"Interpretación visual del material documental; el acabado, tono y parámetros PBR no son una especificación contractual.","note":"La apariencia gráfica no modifica ni confirma la especificación física del material."} | {"elementId":"found_0904_6a94c9fa32a560","ifcGuid":"3OikHGTm9HIQCKXZfHLsh5","ifcClass":"IfcFooting","buildingId":"process_plant","buildingName":"Zona de separación de aire","sourceDocumentId":"LHD2609-JG00100-20260904","sourceRepresentationKind":"foundation"} | {"layerId":"foundations","layerName":"Cimentaciones","role":"Cimentación industrial","basis":"Clasificación por función del elemento; no modifica las especificaciones documentales."} | {"profileId":"concrete_reinforced","name":"Hormigón armado · gris natural","status":"criterio_visual","basis":"Interpretación visual del material documental; el acabado, tono y parámetros PBR no son una especificación contractual.","physicalMaterialUnchanged":true} | 0.176 | Hormigón armado · clase pendiente de confirmar | Hormigón armado · gris natural | found_0904_6a94c9fa32a560 | Geometría de cimentación del fabricante; no se extrapola HA-30 de la nota de pedestales. | Clase no confirmada en la hoja de equipo | concrete_reinforced | [0.666667,0.662745,0.619608] | 0.96 | Zona de separación de aire; BIM · Cimentaciones | 0.450754 | 0.450754 | 1.1 | 286.1 | 287.2 | F-IC-CONTAINER | ["IC-CONTAINER"] | [] | 15–15 | ["5645/5652","1DB82","1DE55"] | F-IC-CONTAINER/Cimentación y plataforma del módulo IC-CONTAINER · pilar KZ1 05 | foundation | Geometría de fabricante; implantación absoluta provisional | IC-CONTAINER | Cimentaciones de equipos y pedestales del fabricante · revisión recibida 04/09/2026 | 5645/5652, 1DB82, 1DE55 | 0 | 1.1 | 0.16 | Cotas relativas del dibujo. La equivalencia con un datum absoluto está pendiente. | Z del modelo = cota relativa + 1,10 m. Correspondencia provisional con 286,10 m; no es cota de obra confirmada. | Sección y contornos del fabricante; incidencias conservadas | 0.4 | 0.4 | La planta general y algunos croquis de apoyo muestran dimensiones transversales distintas. Se usan el contorno de cimentación y los centros de pilares de la implantación general; sección de viga VC1 400 × 400 mm y vuelo a 1050 mm del eje según detalle. / La capa de mortero sobre la losa no tiene una referencia vertical inequívoca; no se duplica una capa independiente en esa losa.
Cimentación y plataforma del módulo IC-CONTAINER · pilar KZ1 06 | Parcela industrial Jinhong | Cimentación industrial | Cimentaciones de equipos y pedestales del fabricante · revisión recibida 04/09/2026 | 0.450754 | 0.450754 | 1.1 | 2.08 | 0.176 | process_plant | Zona de separación de aire | {"name":"Hormigón armado · clase pendiente de confirmar","status":"Clase no confirmada en la hoja de equipo","source":"Geometría de cimentación del fabricante; no se extrapola HA-30 de la nota de pedestales."} | {"documented":[{"label":"Extensión local X","value":0.4,"unit":"m","source":"5645/5652, 1DB82, 1DE55","status":"derivada del contorno CAD"},{"label":"Extensión local Y","value":0.4,"unit":"m","source":"5645/5652, 1DB82, 1DE55","status":"derivada del contorno CAD"},{"label":"Cota inferior relativa adoptada","value":0,"unit":"m","source":"15–15","status":"interpretación con conflicto conservado"},{"label":"Cota superior relativa adoptada","value":1.1,"unit":"m","source":"15–15","status":"documentada / separación por material"}],"geometry":[{"label":"Extensión de la malla en X","value":0.4507539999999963,"unit":"m","source":"Geometría releída del IFC; datum absoluto de proceso provisional","status":"derivado"},{"label":"Extensión de la malla en Y","value":0.4507539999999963,"unit":"m","source":"Geometría releída del IFC; datum absoluto de proceso provisional","status":"derivado"},{"label":"Extensión de la malla en Z","value":1.1,"unit":"m","source":"Geometría releída del IFC; datum absoluto de proceso provisional","status":"derivado"},{"label":"Cota inferior de visualización","value":286.1,"unit":"m","source":"Geometría releída del IFC; datum absoluto de proceso provisional","status":"derivado"},{"label":"Cota superior de visualización","value":287.2,"unit":"m","source":"Geometría releída del IFC; datum absoluto de proceso provisional","status":"derivado"}]} | {"documentId":"LHD2609-JG00100-20260904","title":"Cimentaciones de equipos y pedestales del fabricante · revisión recibida 04/09/2026","date":"2026-09-04","sheet":"15–15","fileName":"LHD2609-JG00100_20260904.dwg","revisionCaveat":"Fecha de revisión tomada del nombre recibido; cajetines internos mantienen 02/07/2026 y algunos textos de plantilla.","sourceFileSha256":"b42eb027b7bc0b14c38d1d13514f4899b58a732aa8d0ba2ccf10fa2fc3192890"} | provisional | ["La planta general y algunos croquis de apoyo muestran dimensiones transversales distintas. Se usan el contorno de cimentación y los centros de pilares de la implantación general; sección de viga VC1 400 × 400 mm y vuelo a 1050 mm del eje según detalle.","La capa de mortero sobre la losa no tiene una referencia vertical inequívoca; no se duplica una capa independiente en esa losa."] | {"Cota inferior relativa (m)":0,"Cota superior relativa (m)":1.1,"Cero absoluto de visualización (m)":286.1,"Estado del cero absoluto":"Provisional","Criterio":"Las cotas relativas proceden del dibujo; la equivalencia absoluta no está confirmada."} | {"boundingBoxM":{"min":[37.847402,62.060115,1.1],"max":[38.298156,62.510869,2.2]},"extentsM":[0.450754,0.450754,1.1],"meshSurfaceM2":2.08,"meshVolumeM3":0.176,"closedSolid":true,"basis":"Magnitudes de las mallas representadas, no cantidades certificadas de obra, compra o fabricación. Las partes pueden compartir superficies; no se suman como un despiece de materiales."} | {"profileId":"concrete_reinforced","name":"Hormigón armado · gris natural","materialName":"Hormigón armado · clase pendiente de confirmar","physicalMaterialStatus":"Clase no confirmada en la hoja de equipo","physicalMaterialSource":"Geometría de cimentación del fabricante; no se extrapola HA-30 de la nota de pedestales.","appearanceStatus":"criterio_visual","appearanceBasis":"Interpretación visual del material documental; el acabado, tono y parámetros PBR no son una especificación contractual.","note":"La apariencia gráfica no modifica ni confirma la especificación física del material."} | {"elementId":"found_0904_9722ff0b284716","ifcGuid":"3L0zkT2wfPAe4Wiv$j6Z66","ifcClass":"IfcFooting","buildingId":"process_plant","buildingName":"Zona de separación de aire","sourceDocumentId":"LHD2609-JG00100-20260904","sourceRepresentationKind":"foundation"} | {"layerId":"foundations","layerName":"Cimentaciones","role":"Cimentación industrial","basis":"Clasificación por función del elemento; no modifica las especificaciones documentales."} | {"profileId":"concrete_reinforced","name":"Hormigón armado · gris natural","status":"criterio_visual","basis":"Interpretación visual del material documental; el acabado, tono y parámetros PBR no son una especificación contractual.","physicalMaterialUnchanged":true} | 0.176 | Hormigón armado · clase pendiente de confirmar | Hormigón armado · gris natural | found_0904_9722ff0b284716 | Geometría de cimentación del fabricante; no se extrapola HA-30 de la nota de pedestales. | Clase no confirmada en la hoja de equipo | concrete_reinforced | [0.666667,0.662745,0.619608] | 0.96 | Zona de separación de aire; BIM · Cimentaciones | 0.450754 | 0.450754 | 1.1 | 286.1 | 287.2 | F-IC-CONTAINER | ["IC-CONTAINER"] | [] | 15–15 | ["5645/5652","1DB82","1DE55"] | F-IC-CONTAINER/Cimentación y plataforma del módulo IC-CONTAINER · pilar KZ1 06 | foundation | Geometría de fabricante; implantación absoluta provisional | IC-CONTAINER | Cimentaciones de equipos y pedestales del fabricante · revisión recibida 04/09/2026 | 5645/5652, 1DB82, 1DE55 | 0 | 1.1 | 0.16 | Cotas relativas del dibujo. La equivalencia con un datum absoluto está pendiente. | Z del modelo = cota relativa + 1,10 m. Correspondencia provisional con 286,10 m; no es cota de obra confirmada. | Sección y contornos del fabricante; incidencias conservadas | 0.4 | 0.4 | La planta general y algunos croquis de apoyo muestran dimensiones transversales distintas. Se usan el contorno de cimentación y los centros de pilares de la implantación general; sección de viga VC1 400 × 400 mm y vuelo a 1050 mm del eje según detalle. / La capa de mortero sobre la losa no tiene una referencia vertical inequívoca; no se duplica una capa independiente en esa losa.
Cimentación y plataforma del módulo IC-CONTAINER · pilar KZ1 07 | Parcela industrial Jinhong | Cimentación industrial | Cimentaciones de equipos y pedestales del fabricante · revisión recibida 04/09/2026 | 0.450754 | 0.450754 | 1.1 | 2.08 | 0.176 | process_plant | Zona de separación de aire | {"name":"Hormigón armado · clase pendiente de confirmar","status":"Clase no confirmada en la hoja de equipo","source":"Geometría de cimentación del fabricante; no se extrapola HA-30 de la nota de pedestales."} | {"documented":[{"label":"Extensión local X","value":0.4,"unit":"m","source":"5645/5652, 1DB82, 1DE55","status":"derivada del contorno CAD"},{"label":"Extensión local Y","value":0.4,"unit":"m","source":"5645/5652, 1DB82, 1DE55","status":"derivada del contorno CAD"},{"label":"Cota inferior relativa adoptada","value":0,"unit":"m","source":"15–15","status":"interpretación con conflicto conservado"},{"label":"Cota superior relativa adoptada","value":1.1,"unit":"m","source":"15–15","status":"documentada / separación por material"}],"geometry":[{"label":"Extensión de la malla en X","value":0.45075400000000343,"unit":"m","source":"Geometría releída del IFC; datum absoluto de proceso provisional","status":"derivado"},{"label":"Extensión de la malla en Y","value":0.45075400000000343,"unit":"m","source":"Geometría releída del IFC; datum absoluto de proceso provisional","status":"derivado"},{"label":"Extensión de la malla en Z","value":1.1,"unit":"m","source":"Geometría releída del IFC; datum absoluto de proceso provisional","status":"derivado"},{"label":"Cota inferior de visualización","value":286.1,"unit":"m","source":"Geometría releída del IFC; datum absoluto de proceso provisional","status":"derivado"},{"label":"Cota superior de visualización","value":287.2,"unit":"m","source":"Geometría releída del IFC; datum absoluto de proceso provisional","status":"derivado"}]} | {"documentId":"LHD2609-JG00100-20260904","title":"Cimentaciones de equipos y pedestales del fabricante · revisión recibida 04/09/2026","date":"2026-09-04","sheet":"15–15","fileName":"LHD2609-JG00100_20260904.dwg","revisionCaveat":"Fecha de revisión tomada del nombre recibido; cajetines internos mantienen 02/07/2026 y algunos textos de plantilla.","sourceFileSha256":"b42eb027b7bc0b14c38d1d13514f4899b58a732aa8d0ba2ccf10fa2fc3192890"} | provisional | ["La planta general y algunos croquis de apoyo muestran dimensiones transversales distintas. Se usan el contorno de cimentación y los centros de pilares de la implantación general; sección de viga VC1 400 × 400 mm y vuelo a 1050 mm del eje según detalle.","La capa de mortero sobre la losa no tiene una referencia vertical inequívoca; no se duplica una capa independiente en esa losa."] | {"Cota inferior relativa (m)":0,"Cota superior relativa (m)":1.1,"Cero absoluto de visualización (m)":286.1,"Estado del cero absoluto":"Provisional","Criterio":"Las cotas relativas proceden del dibujo; la equivalencia absoluta no está confirmada."} | {"boundingBoxM":{"min":[38.186209,64.524434,1.1],"max":[38.636963,64.975188,2.2]},"extentsM":[0.450754,0.450754,1.1],"meshSurfaceM2":2.08,"meshVolumeM3":0.176,"closedSolid":true,"basis":"Magnitudes de las mallas representadas, no cantidades certificadas de obra, compra o fabricación. Las partes pueden compartir superficies; no se suman como un despiece de materiales."} | {"profileId":"concrete_reinforced","name":"Hormigón armado · gris natural","materialName":"Hormigón armado · clase pendiente de confirmar","physicalMaterialStatus":"Clase no confirmada en la hoja de equipo","physicalMaterialSource":"Geometría de cimentación del fabricante; no se extrapola HA-30 de la nota de pedestales.","appearanceStatus":"criterio_visual","appearanceBasis":"Interpretación visual del material documental; el acabado, tono y parámetros PBR no son una especificación contractual.","note":"La apariencia gráfica no modifica ni confirma la especificación física del material."} | {"elementId":"found_0904_da05fb84c57029","ifcGuid":"28ANGfVQ1Rs87b6Xt1N3EZ","ifcClass":"IfcFooting","buildingId":"process_plant","buildingName":"Zona de separación de aire","sourceDocumentId":"LHD2609-JG00100-20260904","sourceRepresentationKind":"foundation"} | {"layerId":"foundations","layerName":"Cimentaciones","role":"Cimentación industrial","basis":"Clasificación por función del elemento; no modifica las especificaciones documentales."} | {"profileId":"concrete_reinforced","name":"Hormigón armado · gris natural","status":"criterio_visual","basis":"Interpretación visual del material documental; el acabado, tono y parámetros PBR no son una especificación contractual.","physicalMaterialUnchanged":true} | 0.176 | Hormigón armado · clase pendiente de confirmar | Hormigón armado · gris natural | found_0904_da05fb84c57029 | Geometría de cimentación del fabricante; no se extrapola HA-30 de la nota de pedestales. | Clase no confirmada en la hoja de equipo | concrete_reinforced | [0.666667,0.662745,0.619608] | 0.96 | Zona de separación de aire; BIM · Cimentaciones | 0.450754 | 0.450754 | 1.1 | 286.1 | 287.2 | F-IC-CONTAINER | ["IC-CONTAINER"] | [] | 15–15 | ["5645/5652","1DB82","1DE55"] | F-IC-CONTAINER/Cimentación y plataforma del módulo IC-CONTAINER · pilar KZ1 07 | foundation | Geometría de fabricante; implantación absoluta provisional | IC-CONTAINER | Cimentaciones de equipos y pedestales del fabricante · revisión recibida 04/09/2026 | 5645/5652, 1DB82, 1DE55 | 0 | 1.1 | 0.16 | Cotas relativas del dibujo. La equivalencia con un datum absoluto está pendiente. | Z del modelo = cota relativa + 1,10 m. Correspondencia provisional con 286,10 m; no es cota de obra confirmada. | Sección y contornos del fabricante; incidencias conservadas | 0.4 | 0.4 | La planta general y algunos croquis de apoyo muestran dimensiones transversales distintas. Se usan el contorno de cimentación y los centros de pilares de la implantación general; sección de viga VC1 400 × 400 mm y vuelo a 1050 mm del eje según detalle. / La capa de mortero sobre la losa no tiene una referencia vertical inequívoca; no se duplica una capa independiente en esa losa.
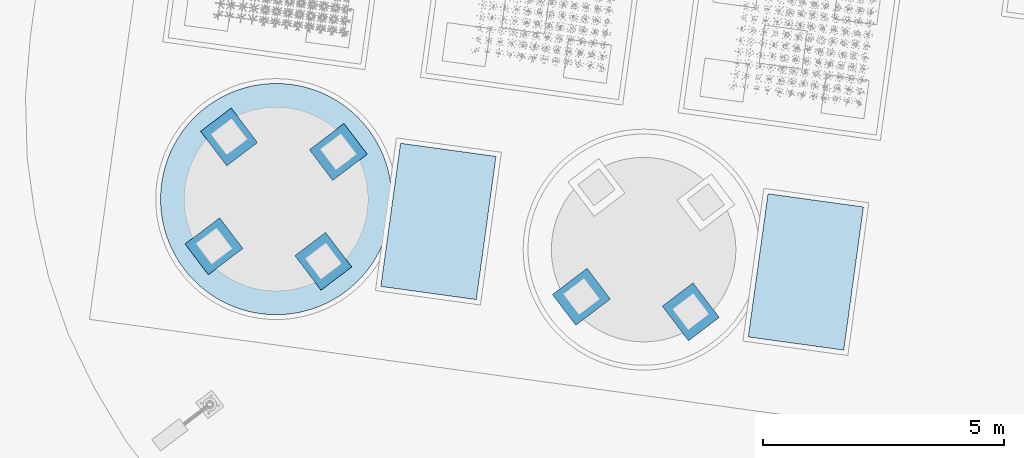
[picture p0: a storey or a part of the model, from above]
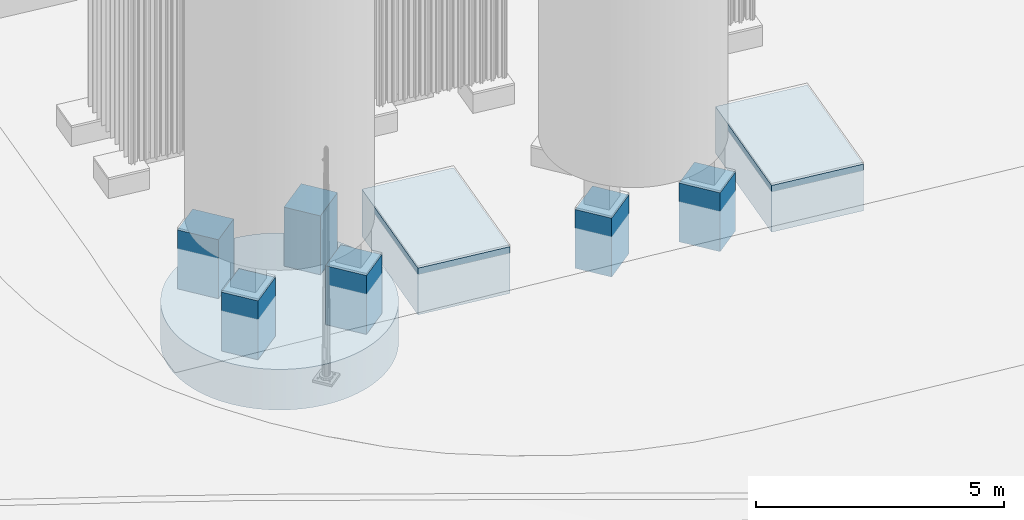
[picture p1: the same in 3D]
Properties of the parts of a building model (IFC4), part 77 of 134

# IfcFooting (214)
Name | In | Description = category = Categoria = Funcion | Document | ExtensionX (m) | ExtensionY (m) | ExtensionZ (m) | SuperficieDeLaMalla (m2) | VolumenGeometrico (m3) | buildingId | buildingName | material | dimensions | JH_InformacionBIM, source = DocumentoFuente | JH_InformacionBIM, status = EstadoDeInformacion | issues = IncidenciasPendientes | positioning = PosicionYEstado | geometryMetrics | materialAppearance | visualizationIdentity | classification | appearance | Volumen geométrico (m³) | JH_Trazabilidad, Material = name | Acabado de visualización = Acabado | Identificador | JH_EvidenciaDeMaterial, source | JH_EvidenciaDeMaterial, status | Perfil | ColorRGB | Rugosidad | Group | Extensión de la malla en X (m) | Extensión de la malla en Y (m) | Extensión de la malla en Z (m) = Espesor o altura real de sección (m) | Cota inferior de visualización (m) | Cota superior de visualización (m) | assemblyId = Conjunto de cimentación | equipmentIds | supportPositionIds | sectionRef = Sección de referencia | sourceCadHandles | stableElementKey | representationKind | geometryStatus | Equipos asociados | Documento de origen | Identificadores CAD de referencia | Cota inferior relativa (m) = Cota inferior relativa adoptada (m) | Cota superior relativa (m) = Cota superior relativa adoptada (m) | Área de planta (m²) | Referencia vertical | Implantación para visualización | Estado de la geometría | Extensión local X (m) | Extensión local Y (m) | Incidencias de origen
Cimentación y plataforma del módulo IC-CONTAINER · pilar KZ1 08 | Parcela industrial Jinhong | Cimentación industrial | Cimentaciones de equipos y pedestales del fabricante · revisión recibida 04/09/2026 | 0.450754 | 0.450754 | 1.1 | 2.08 | 0.176 | process_plant | Zona de separación de aire | {"name":"Hormigón armado · clase pendiente de confirmar","status":"Clase no confirmada en la hoja de equipo","source":"Geometría de cimentación del fabricante; no se extrapola HA-30 de la nota de pedestales."} | {"documented":[{"label":"Extensión local X","value":0.4,"unit":"m","source":"5645/5652, 1DB82, 1DE55","status":"derivada del contorno CAD"},{"label":"Extensión local Y","value":0.4,"unit":"m","source":"5645/5652, 1DB82, 1DE55","status":"derivada del contorno CAD"},{"label":"Cota inferior relativa adoptada","value":0,"unit":"m","source":"15–15","status":"interpretación con conflicto conservado"},{"label":"Cota superior relativa adoptada","value":1.1,"unit":"m","source":"15–15","status":"documentada / separación por material"}],"geometry":[{"label":"Extensión de la malla en X","value":0.4507539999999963,"unit":"m","source":"Geometría releída del IFC; datum absoluto de proceso provisional","status":"derivado"},{"label":"Extensión de la malla en Y","value":0.4507539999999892,"unit":"m","source":"Geometría releída del IFC; datum absoluto de proceso provisional","status":"derivado"},{"label":"Extensión de la malla en Z","value":1.1,"unit":"m","source":"Geometría releída del IFC; datum absoluto de proceso provisional","status":"derivado"},{"label":"Cota inferior de visualización","value":286.1,"unit":"m","source":"Geometría releída del IFC; datum absoluto de proceso provisional","status":"derivado"},{"label":"Cota superior de visualización","value":287.2,"unit":"m","source":"Geometría releída del IFC; datum absoluto de proceso provisional","status":"derivado"}]} | {"documentId":"LHD2609-JG00100-20260904","title":"Cimentaciones de equipos y pedestales del fabricante · revisión recibida 04/09/2026","date":"2026-09-04","sheet":"15–15","fileName":"LHD2609-JG00100_20260904.dwg","revisionCaveat":"Fecha de revisión tomada del nombre recibido; cajetines internos mantienen 02/07/2026 y algunos textos de plantilla.","sourceFileSha256":"b42eb027b7bc0b14c38d1d13514f4899b58a732aa8d0ba2ccf10fa2fc3192890"} | provisional | ["La planta general y algunos croquis de apoyo muestran dimensiones transversales distintas. Se usan el contorno de cimentación y los centros de pilares de la implantación general; sección de viga VC1 400 × 400 mm y vuelo a 1050 mm del eje según detalle.","La capa de mortero sobre la losa no tiene una referencia vertical inequívoca; no se duplica una capa independiente en esa losa."] | {"Cota inferior relativa (m)":0,"Cota superior relativa (m)":1.1,"Cero absoluto de visualización (m)":286.1,"Estado del cero absoluto":"Provisional","Criterio":"Las cotas relativas proceden del dibujo; la equivalencia absoluta no está confirmada."} | {"boundingBoxM":{"min":[38.525016,66.988752,1.1],"max":[38.97577,67.439506,2.2]},"extentsM":[0.450754,0.450754,1.1],"meshSurfaceM2":2.08,"meshVolumeM3":0.176,"closedSolid":true,"basis":"Magnitudes de las mallas representadas, no cantidades certificadas de obra, compra o fabricación. Las partes pueden compartir superficies; no se suman como un despiece de materiales."} | {"profileId":"concrete_reinforced","name":"Hormigón armado · gris natural","materialName":"Hormigón armado · clase pendiente de confirmar","physicalMaterialStatus":"Clase no confirmada en la hoja de equipo","physicalMaterialSource":"Geometría de cimentación del fabricante; no se extrapola HA-30 de la nota de pedestales.","appearanceStatus":"criterio_visual","appearanceBasis":"Interpretación visual del material documental; el acabado, tono y parámetros PBR no son una especificación contractual.","note":"La apariencia gráfica no modifica ni confirma la especificación física del material."} | {"elementId":"found_0904_cf7cdc7477904e","ifcGuid":"0kMQC8k6fOMwkfKHaR0T4D","ifcClass":"IfcFooting","buildingId":"process_plant","buildingName":"Zona de separación de aire","sourceDocumentId":"LHD2609-JG00100-20260904","sourceRepresentationKind":"foundation"} | {"layerId":"foundations","layerName":"Cimentaciones","role":"Cimentación industrial","basis":"Clasificación por función del elemento; no modifica las especificaciones documentales."} | {"profileId":"concrete_reinforced","name":"Hormigón armado · gris natural","status":"criterio_visual","basis":"Interpretación visual del material documental; el acabado, tono y parámetros PBR no son una especificación contractual.","physicalMaterialUnchanged":true} | 0.176 | Hormigón armado · clase pendiente de confirmar | Hormigón armado · gris natural | found_0904_cf7cdc7477904e | Geometría de cimentación del fabricante; no se extrapola HA-30 de la nota de pedestales. | Clase no confirmada en la hoja de equipo | concrete_reinforced | [0.666667,0.662745,0.619608] | 0.96 | Zona de separación de aire; BIM · Cimentaciones | 0.450754 | 0.450754 | 1.1 | 286.1 | 287.2 | F-IC-CONTAINER | ["IC-CONTAINER"] | [] | 15–15 | ["5645/5652","1DB82","1DE55"] | F-IC-CONTAINER/Cimentación y plataforma del módulo IC-CONTAINER · pilar KZ1 08 | foundation | Geometría de fabricante; implantación absoluta provisional | IC-CONTAINER | Cimentaciones de equipos y pedestales del fabricante · revisión recibida 04/09/2026 | 5645/5652, 1DB82, 1DE55 | 0 | 1.1 | 0.16 | Cotas relativas del dibujo. La equivalencia con un datum absoluto está pendiente. | Z del modelo = cota relativa + 1,10 m. Correspondencia provisional con 286,10 m; no es cota de obra confirmada. | Sección y contornos del fabricante; incidencias conservadas | 0.4 | 0.4 | La planta general y algunos croquis de apoyo muestran dimensiones transversales distintas. Se usan el contorno de cimentación y los centros de pilares de la implantación general; sección de viga VC1 400 × 400 mm y vuelo a 1050 mm del eje según detalle. / La capa de mortero sobre la losa no tiene una referencia vertical inequívoca; no se duplica una capa independiente en esa losa.
Cimentación y plataforma del módulo IC-CONTAINER · pilar KZ1 09 | Parcela industrial Jinhong | Cimentación industrial | Cimentaciones de equipos y pedestales del fabricante · revisión recibida 04/09/2026 | 0.450753 | 0.450754 | 1.1 | 2.08 | 0.176 | process_plant | Zona de separación de aire | {"name":"Hormigón armado · clase pendiente de confirmar","status":"Clase no confirmada en la hoja de equipo","source":"Geometría de cimentación del fabricante; no se extrapola HA-30 de la nota de pedestales."} | {"documented":[{"label":"Extensión local X","value":0.4,"unit":"m","source":"5645/5652, 1DB82, 1DE55","status":"derivada del contorno CAD"},{"label":"Extensión local Y","value":0.4,"unit":"m","source":"5645/5652, 1DB82, 1DE55","status":"derivada del contorno CAD"},{"label":"Cota inferior relativa adoptada","value":0,"unit":"m","source":"15–15","status":"interpretación con conflicto conservado"},{"label":"Cota superior relativa adoptada","value":1.1,"unit":"m","source":"15–15","status":"documentada / separación por material"}],"geometry":[{"label":"Extensión de la malla en X","value":0.45075299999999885,"unit":"m","source":"Geometría releída del IFC; datum absoluto de proceso provisional","status":"derivado"},{"label":"Extensión de la malla en Y","value":0.45075400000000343,"unit":"m","source":"Geometría releída del IFC; datum absoluto de proceso provisional","status":"derivado"},{"label":"Extensión de la malla en Z","value":1.1,"unit":"m","source":"Geometría releída del IFC; datum absoluto de proceso provisional","status":"derivado"},{"label":"Cota inferior de visualización","value":286.1,"unit":"m","source":"Geometría releída del IFC; datum absoluto de proceso provisional","status":"derivado"},{"label":"Cota superior de visualización","value":287.2,"unit":"m","source":"Geometría releída del IFC; datum absoluto de proceso provisional","status":"derivado"}]} | {"documentId":"LHD2609-JG00100-20260904","title":"Cimentaciones de equipos y pedestales del fabricante · revisión recibida 04/09/2026","date":"2026-09-04","sheet":"15–15","fileName":"LHD2609-JG00100_20260904.dwg","revisionCaveat":"Fecha de revisión tomada del nombre recibido; cajetines internos mantienen 02/07/2026 y algunos textos de plantilla.","sourceFileSha256":"b42eb027b7bc0b14c38d1d13514f4899b58a732aa8d0ba2ccf10fa2fc3192890"} | provisional | ["La planta general y algunos croquis de apoyo muestran dimensiones transversales distintas. Se usan el contorno de cimentación y los centros de pilares de la implantación general; sección de viga VC1 400 × 400 mm y vuelo a 1050 mm del eje según detalle.","La capa de mortero sobre la losa no tiene una referencia vertical inequívoca; no se duplica una capa independiente en esa losa."] | {"Cota inferior relativa (m)":0,"Cota superior relativa (m)":1.1,"Cero absoluto de visualización (m)":286.1,"Estado del cero absoluto":"Provisional","Criterio":"Las cotas relativas proceden del dibujo; la equivalencia absoluta no está confirmada."} | {"boundingBoxM":{"min":[38.863824,69.453071,1.1],"max":[39.314577,69.903825,2.2]},"extentsM":[0.450753,0.450754,1.1],"meshSurfaceM2":2.079999,"meshVolumeM3":0.176,"closedSolid":true,"basis":"Magnitudes de las mallas representadas, no cantidades certificadas de obra, compra o fabricación. Las partes pueden compartir superficies; no se suman como un despiece de materiales."} | {"profileId":"concrete_reinforced","name":"Hormigón armado · gris natural","materialName":"Hormigón armado · clase pendiente de confirmar","physicalMaterialStatus":"Clase no confirmada en la hoja de equipo","physicalMaterialSource":"Geometría de cimentación del fabricante; no se extrapola HA-30 de la nota de pedestales.","appearanceStatus":"criterio_visual","appearanceBasis":"Interpretación visual del material documental; el acabado, tono y parámetros PBR no son una especificación contractual.","note":"La apariencia gráfica no modifica ni confirma la especificación física del material."} | {"elementId":"found_0904_46423874b3d85e","ifcGuid":"39dxZh3wDSdwN6xzSdMi3A","ifcClass":"IfcFooting","buildingId":"process_plant","buildingName":"Zona de separación de aire","sourceDocumentId":"LHD2609-JG00100-20260904","sourceRepresentationKind":"foundation"} | {"layerId":"foundations","layerName":"Cimentaciones","role":"Cimentación industrial","basis":"Clasificación por función del elemento; no modifica las especificaciones documentales."} | {"profileId":"concrete_reinforced","name":"Hormigón armado · gris natural","status":"criterio_visual","basis":"Interpretación visual del material documental; el acabado, tono y parámetros PBR no son una especificación contractual.","physicalMaterialUnchanged":true} | 0.176 | Hormigón armado · clase pendiente de confirmar | Hormigón armado · gris natural | found_0904_46423874b3d85e | Geometría de cimentación del fabricante; no se extrapola HA-30 de la nota de pedestales. | Clase no confirmada en la hoja de equipo | concrete_reinforced | [0.666667,0.662745,0.619608] | 0.96 | Zona de separación de aire; BIM · Cimentaciones | 0.450753 | 0.450754 | 1.1 | 286.1 | 287.2 | F-IC-CONTAINER | ["IC-CONTAINER"] | [] | 15–15 | ["5645/5652","1DB82","1DE55"] | F-IC-CONTAINER/Cimentación y plataforma del módulo IC-CONTAINER · pilar KZ1 09 | foundation | Geometría de fabricante; implantación absoluta provisional | IC-CONTAINER | Cimentaciones de equipos y pedestales del fabricante · revisión recibida 04/09/2026 | 5645/5652, 1DB82, 1DE55 | 0 | 1.1 | 0.16 | Cotas relativas del dibujo. La equivalencia con un datum absoluto está pendiente. | Z del modelo = cota relativa + 1,10 m. Correspondencia provisional con 286,10 m; no es cota de obra confirmada. | Sección y contornos del fabricante; incidencias conservadas | 0.4 | 0.4 | La planta general y algunos croquis de apoyo muestran dimensiones transversales distintas. Se usan el contorno de cimentación y los centros de pilares de la implantación general; sección de viga VC1 400 × 400 mm y vuelo a 1050 mm del eje según detalle. / La capa de mortero sobre la losa no tiene una referencia vertical inequívoca; no se duplica una capa independiente en esa losa.
Cimentación y plataforma del módulo IC-CONTAINER · pilar KZ1 10 | Parcela industrial Jinhong | Cimentación industrial | Cimentaciones de equipos y pedestales del fabricante · revisión recibida 04/09/2026 | 0.450754 | 0.450754 | 1.1 | 2.08 | 0.176 | process_plant | Zona de separación de aire | {"name":"Hormigón armado · clase pendiente de confirmar","status":"Clase no confirmada en la hoja de equipo","source":"Geometría de cimentación del fabricante; no se extrapola HA-30 de la nota de pedestales."} | {"documented":[{"label":"Extensión local X","value":0.4,"unit":"m","source":"5645/5652, 1DB82, 1DE55","status":"derivada del contorno CAD"},{"label":"Extensión local Y","value":0.4,"unit":"m","source":"5645/5652, 1DB82, 1DE55","status":"derivada del contorno CAD"},{"label":"Cota inferior relativa adoptada","value":0,"unit":"m","source":"15–15","status":"interpretación con conflicto conservado"},{"label":"Cota superior relativa adoptada","value":1.1,"unit":"m","source":"15–15","status":"documentada / separación por material"}],"geometry":[{"label":"Extensión de la malla en X","value":0.45075400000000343,"unit":"m","source":"Geometría releída del IFC; datum absoluto de proceso provisional","status":"derivado"},{"label":"Extensión de la malla en Y","value":0.45075400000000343,"unit":"m","source":"Geometría releída del IFC; datum absoluto de proceso provisional","status":"derivado"},{"label":"Extensión de la malla en Z","value":1.1,"unit":"m","source":"Geometría releída del IFC; datum absoluto de proceso provisional","status":"derivado"},{"label":"Cota inferior de visualización","value":286.1,"unit":"m","source":"Geometría releída del IFC; datum absoluto de proceso provisional","status":"derivado"},{"label":"Cota superior de visualización","value":287.2,"unit":"m","source":"Geometría releída del IFC; datum absoluto de proceso provisional","status":"derivado"}]} | {"documentId":"LHD2609-JG00100-20260904","title":"Cimentaciones de equipos y pedestales del fabricante · revisión recibida 04/09/2026","date":"2026-09-04","sheet":"15–15","fileName":"LHD2609-JG00100_20260904.dwg","revisionCaveat":"Fecha de revisión tomada del nombre recibido; cajetines internos mantienen 02/07/2026 y algunos textos de plantilla.","sourceFileSha256":"b42eb027b7bc0b14c38d1d13514f4899b58a732aa8d0ba2ccf10fa2fc3192890"} | provisional | ["La planta general y algunos croquis de apoyo muestran dimensiones transversales distintas. Se usan el contorno de cimentación y los centros de pilares de la implantación general; sección de viga VC1 400 × 400 mm y vuelo a 1050 mm del eje según detalle.","La capa de mortero sobre la losa no tiene una referencia vertical inequívoca; no se duplica una capa independiente en esa losa."] | {"Cota inferior relativa (m)":0,"Cota superior relativa (m)":1.1,"Cero absoluto de visualización (m)":286.1,"Estado del cero absoluto":"Provisional","Criterio":"Las cotas relativas proceden del dibujo; la equivalencia absoluta no está confirmada."} | {"boundingBoxM":{"min":[39.202631,71.917389,1.1],"max":[39.653385,72.368143,2.2]},"extentsM":[0.450754,0.450754,1.1],"meshSurfaceM2":2.080001,"meshVolumeM3":0.176,"closedSolid":true,"basis":"Magnitudes de las mallas representadas, no cantidades certificadas de obra, compra o fabricación. Las partes pueden compartir superficies; no se suman como un despiece de materiales."} | {"profileId":"concrete_reinforced","name":"Hormigón armado · gris natural","materialName":"Hormigón armado · clase pendiente de confirmar","physicalMaterialStatus":"Clase no confirmada en la hoja de equipo","physicalMaterialSource":"Geometría de cimentación del fabricante; no se extrapola HA-30 de la nota de pedestales.","appearanceStatus":"criterio_visual","appearanceBasis":"Interpretación visual del material documental; el acabado, tono y parámetros PBR no son una especificación contractual.","note":"La apariencia gráfica no modifica ni confirma la especificación física del material."} | {"elementId":"found_0904_aeb5610b3d5f11","ifcGuid":"239Zyyr8XQMu0T557Y2oJ1","ifcClass":"IfcFooting","buildingId":"process_plant","buildingName":"Zona de separación de aire","sourceDocumentId":"LHD2609-JG00100-20260904","sourceRepresentationKind":"foundation"} | {"layerId":"foundations","layerName":"Cimentaciones","role":"Cimentación industrial","basis":"Clasificación por función del elemento; no modifica las especificaciones documentales."} | {"profileId":"concrete_reinforced","name":"Hormigón armado · gris natural","status":"criterio_visual","basis":"Interpretación visual del material documental; el acabado, tono y parámetros PBR no son una especificación contractual.","physicalMaterialUnchanged":true} | 0.176 | Hormigón armado · clase pendiente de confirmar | Hormigón armado · gris natural | found_0904_aeb5610b3d5f11 | Geometría de cimentación del fabricante; no se extrapola HA-30 de la nota de pedestales. | Clase no confirmada en la hoja de equipo | concrete_reinforced | [0.666667,0.662745,0.619608] | 0.96 | Zona de separación de aire; BIM · Cimentaciones | 0.450754 | 0.450754 | 1.1 | 286.1 | 287.2 | F-IC-CONTAINER | ["IC-CONTAINER"] | [] | 15–15 | ["5645/5652","1DB82","1DE55"] | F-IC-CONTAINER/Cimentación y plataforma del módulo IC-CONTAINER · pilar KZ1 10 | foundation | Geometría de fabricante; implantación absoluta provisional | IC-CONTAINER | Cimentaciones de equipos y pedestales del fabricante · revisión recibida 04/09/2026 | 5645/5652, 1DB82, 1DE55 | 0 | 1.1 | 0.16 | Cotas relativas del dibujo. La equivalencia con un datum absoluto está pendiente. | Z del modelo = cota relativa + 1,10 m. Correspondencia provisional con 286,10 m; no es cota de obra confirmada. | Sección y contornos del fabricante; incidencias conservadas | 0.4 | 0.4 | La planta general y algunos croquis de apoyo muestran dimensiones transversales distintas. Se usan el contorno de cimentación y los centros de pilares de la implantación general; sección de viga VC1 400 × 400 mm y vuelo a 1050 mm del eje según detalle. / La capa de mortero sobre la losa no tiene una referencia vertical inequívoca; no se duplica una capa independiente en esa losa.
Cimentación y plataforma del módulo MV-CONTAINER · cuerpo de hormigón | Parcela industrial Jinhong | Cimentación industrial | Cimentaciones de equipos y pedestales del fabricante · revisión recibida 04/09/2026 | 10.1337 | 5.83992 | 1 | 116.19 | 43.92 | process_plant | Zona de separación de aire | {"name":"Hormigón armado · clase pendiente de confirmar","status":"Clase no confirmada en la hoja de equipo","source":"Geometría de cimentación del fabricante; no se extrapola HA-30 de la nota de pedestales."} | {"documented":[{"label":"Extensión local X","value":9.6,"unit":"m","source":"5599/559F, 1DB82, 1DE55","status":"derivada del contorno CAD"},{"label":"Extensión local Y","value":4.575,"unit":"m","source":"5599/559F, 1DB82, 1DE55","status":"derivada del contorno CAD"},{"label":"Cota inferior relativa adoptada","value":-1,"unit":"m","source":"16–16","status":"interpretación con conflicto conservado"},{"label":"Cota superior relativa adoptada","value":0,"unit":"m","source":"16–16","status":"documentada / separación por material"}],"geometry":[{"label":"Extensión de la malla en X","value":10.133668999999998,"unit":"m","source":"Geometría releída del IFC; datum absoluto de proceso provisional","status":"derivado"},{"label":"Extensión de la malla en Y","value":5.839921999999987,"unit":"m","source":"Geometría releída del IFC; datum absoluto de proceso provisional","status":"derivado"},{"label":"Extensión de la malla en Z","value":1.0,"unit":"m","source":"Geometría releída del IFC; datum absoluto de proceso provisional","status":"derivado"},{"label":"Cota inferior de visualización","value":285.1,"unit":"m","source":"Geometría releída del IFC; datum absoluto de proceso provisional","status":"derivado"},{"label":"Cota superior de visualización","value":286.1,"unit":"m","source":"Geometría releída del IFC; datum absoluto de proceso provisional","status":"derivado"}]} | {"documentId":"LHD2609-JG00100-20260904","title":"Cimentaciones de equipos y pedestales del fabricante · revisión recibida 04/09/2026","date":"2026-09-04","sheet":"16–16","fileName":"LHD2609-JG00100_20260904.dwg","revisionCaveat":"Fecha de revisión tomada del nombre recibido; cajetines internos mantienen 02/07/2026 y algunos textos de plantilla.","sourceFileSha256":"b42eb027b7bc0b14c38d1d13514f4899b58a732aa8d0ba2ccf10fa2fc3192890"} | provisional | ["La planta general y algunos croquis de apoyo muestran dimensiones transversales distintas. Se usan el contorno de cimentación y los centros de pilares de la implantación general; sección de viga VC1 400 × 400 mm y vuelo a 1050 mm del eje según detalle.","La capa de mortero sobre la losa no tiene una referencia vertical inequívoca; no se duplica una capa independiente en esa losa."] | {"Cota inferior relativa (m)":-1,"Cota superior relativa (m)":0,"Cero absoluto de visualización (m)":286.1,"Estado del cero absoluto":"Provisional","Criterio":"Las cotas relativas proceden del dibujo; la equivalencia absoluta no está confirmada."} | {"boundingBoxM":{"min":[44.718224,79.949599,0.1],"max":[54.851893,85.789521,1.1]},"extentsM":[10.133669,5.839922,1.0],"meshSurfaceM2":116.189996,"meshVolumeM3":43.919998,"closedSolid":true,"basis":"Magnitudes de las mallas representadas, no cantidades certificadas de obra, compra o fabricación. Las partes pueden compartir superficies; no se suman como un despiece de materiales."} | {"profileId":"concrete_reinforced","name":"Hormigón armado · gris natural","materialName":"Hormigón armado · clase pendiente de confirmar","physicalMaterialStatus":"Clase no confirmada en la hoja de equipo","physicalMaterialSource":"Geometría de cimentación del fabricante; no se extrapola HA-30 de la nota de pedestales.","appearanceStatus":"criterio_visual","appearanceBasis":"Interpretación visual del material documental; el acabado, tono y parámetros PBR no son una especificación contractual.","note":"La apariencia gráfica no modifica ni confirma la especificación física del material."} | {"elementId":"found_0904_5fd42e9cd85676","ifcGuid":"1lh8KAkO5OIP2pzqPFEL2l","ifcClass":"IfcFooting","buildingId":"process_plant","buildingName":"Zona de separación de aire","sourceDocumentId":"LHD2609-JG00100-20260904","sourceRepresentationKind":"foundation"} | {"layerId":"foundations","layerName":"Cimentaciones","role":"Cimentación industrial","basis":"Clasificación por función del elemento; no modifica las especificaciones documentales."} | {"profileId":"concrete_reinforced","name":"Hormigón armado · gris natural","status":"criterio_visual","basis":"Interpretación visual del material documental; el acabado, tono y parámetros PBR no son una especificación contractual.","physicalMaterialUnchanged":true} | 43.92 | Hormigón armado · clase pendiente de confirmar | Hormigón armado · gris natural | found_0904_5fd42e9cd85676 | Geometría de cimentación del fabricante; no se extrapola HA-30 de la nota de pedestales. | Clase no confirmada en la hoja de equipo | concrete_reinforced | [0.666667,0.662745,0.619608] | 0.96 | Zona de separación de aire; BIM · Cimentaciones | 10.1337 | 5.83992 | 1 | 285.1 | 286.1 | F-MV-CONTAINER | ["MV-CONTAINER"] | [] | 16–16 | ["5599/559F","1DB82","1DE55"] | F-MV-CONTAINER/Cimentación y plataforma del módulo MV-CONTAINER · cuerpo de hormigón | foundation | Geometría de fabricante; implantación absoluta provisional | MV-CONTAINER | Cimentaciones de equipos y pedestales del fabricante · revisión recibida 04/09/2026 | 5599/559F, 1DB82, 1DE55 | -1 | 0 | 43.92 | Cotas relativas del dibujo. La equivalencia con un datum absoluto está pendiente. | Z del modelo = cota relativa + 1,10 m. Correspondencia provisional con 286,10 m; no es cota de obra confirmada. | Sección y contornos del fabricante; incidencias conservadas | 9.6 | 4.575 | La planta general y algunos croquis de apoyo muestran dimensiones transversales distintas. Se usan el contorno de cimentación y los centros de pilares de la implantación general; sección de viga VC1 400 × 400 mm y vuelo a 1050 mm del eje según detalle. / La capa de mortero sobre la losa no tiene una referencia vertical inequívoca; no se duplica una capa independiente en esa losa.
Cimentación y plataforma del módulo MV-CONTAINER · pilar KZ1 01 | Parcela industrial Jinhong | Cimentación industrial | Cimentaciones de equipos y pedestales del fabricante · revisión recibida 04/09/2026 | 0.450754 | 0.450754 | 1.1 | 2.08 | 0.176 | process_plant | Zona de separación de aire | {"name":"Hormigón armado · clase pendiente de confirmar","status":"Clase no confirmada en la hoja de equipo","source":"Geometría de cimentación del fabricante; no se extrapola HA-30 de la nota de pedestales."} | {"documented":[{"label":"Extensión local X","value":0.4,"unit":"m","source":"5599/559F, 1DB82, 1DE55","status":"derivada del contorno CAD"},{"label":"Extensión local Y","value":0.4,"unit":"m","source":"5599/559F, 1DB82, 1DE55","status":"derivada del contorno CAD"},{"label":"Cota inferior relativa adoptada","value":0,"unit":"m","source":"16–16","status":"interpretación con conflicto conservado"},{"label":"Cota superior relativa adoptada","value":1.1,"unit":"m","source":"16–16","status":"documentada / separación por material"}],"geometry":[{"label":"Extensión de la malla en X","value":0.4507539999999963,"unit":"m","source":"Geometría releída del IFC; datum absoluto de proceso provisional","status":"derivado"},{"label":"Extensión de la malla en Y","value":0.45075400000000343,"unit":"m","source":"Geometría releída del IFC; datum absoluto de proceso provisional","status":"derivado"},{"label":"Extensión de la malla en Z","value":1.1,"unit":"m","source":"Geometría releída del IFC; datum absoluto de proceso provisional","status":"derivado"},{"label":"Cota inferior de visualización","value":286.1,"unit":"m","source":"Geometría releída del IFC; datum absoluto de proceso provisional","status":"derivado"},{"label":"Cota superior de visualización","value":287.2,"unit":"m","source":"Geometría releída del IFC; datum absoluto de proceso provisional","status":"derivado"}]} | {"documentId":"LHD2609-JG00100-20260904","title":"Cimentaciones de equipos y pedestales del fabricante · revisión recibida 04/09/2026","date":"2026-09-04","sheet":"16–16","fileName":"LHD2609-JG00100_20260904.dwg","revisionCaveat":"Fecha de revisión tomada del nombre recibido; cajetines internos mantienen 02/07/2026 y algunos textos de plantilla.","sourceFileSha256":"b42eb027b7bc0b14c38d1d13514f4899b58a732aa8d0ba2ccf10fa2fc3192890"} | provisional | ["La planta general y algunos croquis de apoyo muestran dimensiones transversales distintas. Se usan el contorno de cimentación y los centros de pilares de la implantación general; sección de viga VC1 400 × 400 mm y vuelo a 1050 mm del eje según detalle.","La capa de mortero sobre la losa no tiene una referencia vertical inequívoca; no se duplica una capa independiente en esa losa."] | {"Cota inferior relativa (m)":0,"Cota superior relativa (m)":1.1,"Cero absoluto de visualización (m)":286.1,"Estado del cero absoluto":"Provisional","Criterio":"Las cotas relativas proceden del dibujo; la equivalencia absoluta no está confirmada."} | {"boundingBoxM":{"min":[50.634894,83.669793,1.1],"max":[51.085648,84.120547,2.2]},"extentsM":[0.450754,0.450754,1.1],"meshSurfaceM2":2.080001,"meshVolumeM3":0.176,"closedSolid":true,"basis":"Magnitudes de las mallas representadas, no cantidades certificadas de obra, compra o fabricación. Las partes pueden compartir superficies; no se suman como un despiece de materiales."} | {"profileId":"concrete_reinforced","name":"Hormigón armado · gris natural","materialName":"Hormigón armado · clase pendiente de confirmar","physicalMaterialStatus":"Clase no confirmada en la hoja de equipo","physicalMaterialSource":"Geometría de cimentación del fabricante; no se extrapola HA-30 de la nota de pedestales.","appearanceStatus":"criterio_visual","appearanceBasis":"Interpretación visual del material documental; el acabado, tono y parámetros PBR no son una especificación contractual.","note":"La apariencia gráfica no modifica ni confirma la especificación física del material."} | {"elementId":"found_0904_bb4b2f457d76a6","ifcGuid":"2xgJGLPJHHrOILK483mucE","ifcClass":"IfcFooting","buildingId":"process_plant","buildingName":"Zona de separación de aire","sourceDocumentId":"LHD2609-JG00100-20260904","sourceRepresentationKind":"foundation"} | {"layerId":"foundations","layerName":"Cimentaciones","role":"Cimentación industrial","basis":"Clasificación por función del elemento; no modifica las especificaciones documentales."} | {"profileId":"concrete_reinforced","name":"Hormigón armado · gris natural","status":"criterio_visual","basis":"Interpretación visual del material documental; el acabado, tono y parámetros PBR no son una especificación contractual.","physicalMaterialUnchanged":true} | 0.176 | Hormigón armado · clase pendiente de confirmar | Hormigón armado · gris natural | found_0904_bb4b2f457d76a6 | Geometría de cimentación del fabricante; no se extrapola HA-30 de la nota de pedestales. | Clase no confirmada en la hoja de equipo | concrete_reinforced | [0.666667,0.662745,0.619608] | 0.96 | Zona de separación de aire; BIM · Cimentaciones | 0.450754 | 0.450754 | 1.1 | 286.1 | 287.2 | F-MV-CONTAINER | ["MV-CONTAINER"] | [] | 16–16 | ["5599/559F","1DB82","1DE55"] | F-MV-CONTAINER/Cimentación y plataforma del módulo MV-CONTAINER · pilar KZ1 01 | foundation | Geometría de fabricante; implantación absoluta provisional | MV-CONTAINER | Cimentaciones de equipos y pedestales del fabricante · revisión recibida 04/09/2026 | 5599/559F, 1DB82, 1DE55 | 0 | 1.1 | 0.16 | Cotas relativas del dibujo. La equivalencia con un datum absoluto está pendiente. | Z del modelo = cota relativa + 1,10 m. Correspondencia provisional con 286,10 m; no es cota de obra confirmada. | Sección y contornos del fabricante; incidencias conservadas | 0.4 | 0.4 | La planta general y algunos croquis de apoyo muestran dimensiones transversales distintas. Se usan el contorno de cimentación y los centros de pilares de la implantación general; sección de viga VC1 400 × 400 mm y vuelo a 1050 mm del eje según detalle. / La capa de mortero sobre la losa no tiene una referencia vertical inequívoca; no se duplica una capa independiente en esa losa.
Cimentación y plataforma del módulo MV-CONTAINER · pilar KZ1 02 | Parcela industrial Jinhong | Cimentación industrial | Cimentaciones de equipos y pedestales del fabricante · revisión recibida 04/09/2026 | 0.450754 | 0.450754 | 1.1 | 2.08 | 0.176 | process_plant | Zona de separación de aire | {"name":"Hormigón armado · clase pendiente de confirmar","status":"Clase no confirmada en la hoja de equipo","source":"Geometría de cimentación del fabricante; no se extrapola HA-30 de la nota de pedestales."} | {"documented":[{"label":"Extensión local X","value":0.4,"unit":"m","source":"5599/559F, 1DB82, 1DE55","status":"derivada del contorno CAD"},{"label":"Extensión local Y","value":0.4,"unit":"m","source":"5599/559F, 1DB82, 1DE55","status":"derivada del contorno CAD"},{"label":"Cota inferior relativa adoptada","value":0,"unit":"m","source":"16–16","status":"interpretación con conflicto conservado"},{"label":"Cota superior relativa adoptada","value":1.1,"unit":"m","source":"16–16","status":"documentada / separación por material"}],"geometry":[{"label":"Extensión de la malla en X","value":0.45075400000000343,"unit":"m","source":"Geometría releída del IFC; datum absoluto de proceso provisional","status":"derivado"},{"label":"Extensión de la malla en Y","value":0.4507539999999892,"unit":"m","source":"Geometría releída del IFC; datum absoluto de proceso provisional","status":"derivado"},{"label":"Extensión de la malla en Z","value":1.1,"unit":"m","source":"Geometría releída del IFC; datum absoluto de proceso provisional","status":"derivado"},{"label":"Cota inferior de visualización","value":286.1,"unit":"m","source":"Geometría releída del IFC; datum absoluto de proceso provisional","status":"derivado"},{"label":"Cota superior de visualización","value":287.2,"unit":"m","source":"Geometría releída del IFC; datum absoluto de proceso provisional","status":"derivado"}]} | {"documentId":"LHD2609-JG00100-20260904","title":"Cimentaciones de equipos y pedestales del fabricante · revisión recibida 04/09/2026","date":"2026-09-04","sheet":"16–16","fileName":"LHD2609-JG00100_20260904.dwg","revisionCaveat":"Fecha de revisión tomada del nombre recibido; cajetines internos mantienen 02/07/2026 y algunos textos de plantilla.","sourceFileSha256":"b42eb027b7bc0b14c38d1d13514f4899b58a732aa8d0ba2ccf10fa2fc3192890"} | provisional | ["La planta general y algunos croquis de apoyo muestran dimensiones transversales distintas. Se usan el contorno de cimentación y los centros de pilares de la implantación general; sección de viga VC1 400 × 400 mm y vuelo a 1050 mm del eje según detalle.","La capa de mortero sobre la losa no tiene una referencia vertical inequívoca; no se duplica una capa independiente en esa losa."] | {"Cota inferior relativa (m)":0,"Cota superior relativa (m)":1.1,"Cero absoluto de visualización (m)":286.1,"Estado del cero absoluto":"Provisional","Criterio":"Las cotas relativas proceden del dibujo; la equivalencia absoluta no está confirmada."} | {"boundingBoxM":{"min":[46.889049,81.207041,1.1],"max":[47.339803,81.657795,2.2]},"extentsM":[0.450754,0.450754,1.1],"meshSurfaceM2":2.08,"meshVolumeM3":0.176,"closedSolid":true,"basis":"Magnitudes de las mallas representadas, no cantidades certificadas de obra, compra o fabricación. Las partes pueden compartir superficies; no se suman como un despiece de materiales."} | {"profileId":"concrete_reinforced","name":"Hormigón armado · gris natural","materialName":"Hormigón armado · clase pendiente de confirmar","physicalMaterialStatus":"Clase no confirmada en la hoja de equipo","physicalMaterialSource":"Geometría de cimentación del fabricante; no se extrapola HA-30 de la nota de pedestales.","appearanceStatus":"criterio_visual","appearanceBasis":"Interpretación visual del material documental; el acabado, tono y parámetros PBR no son una especificación contractual.","note":"La apariencia gráfica no modifica ni confirma la especificación física del material."} | {"elementId":"found_0904_e71532bfce3483","ifcGuid":"16KjcfrODJXQ6zbrYl$Alk","ifcClass":"IfcFooting","buildingId":"process_plant","buildingName":"Zona de separación de aire","sourceDocumentId":"LHD2609-JG00100-20260904","sourceRepresentationKind":"foundation"} | {"layerId":"foundations","layerName":"Cimentaciones","role":"Cimentación industrial","basis":"Clasificación por función del elemento; no modifica las especificaciones documentales."} | {"profileId":"concrete_reinforced","name":"Hormigón armado · gris natural","status":"criterio_visual","basis":"Interpretación visual del material documental; el acabado, tono y parámetros PBR no son una especificación contractual.","physicalMaterialUnchanged":true} | 0.176 | Hormigón armado · clase pendiente de confirmar | Hormigón armado · gris natural | found_0904_e71532bfce3483 | Geometría de cimentación del fabricante; no se extrapola HA-30 de la nota de pedestales. | Clase no confirmada en la hoja de equipo | concrete_reinforced | [0.666667,0.662745,0.619608] | 0.96 | Zona de separación de aire; BIM · Cimentaciones | 0.450754 | 0.450754 | 1.1 | 286.1 | 287.2 | F-MV-CONTAINER | ["MV-CONTAINER"] | [] | 16–16 | ["5599/559F","1DB82","1DE55"] | F-MV-CONTAINER/Cimentación y plataforma del módulo MV-CONTAINER · pilar KZ1 02 | foundation | Geometría de fabricante; implantación absoluta provisional | MV-CONTAINER | Cimentaciones de equipos y pedestales del fabricante · revisión recibida 04/09/2026 | 5599/559F, 1DB82, 1DE55 | 0 | 1.1 | 0.16 | Cotas relativas del dibujo. La equivalencia con un datum absoluto está pendiente. | Z del modelo = cota relativa + 1,10 m. Correspondencia provisional con 286,10 m; no es cota de obra confirmada. | Sección y contornos del fabricante; incidencias conservadas | 0.4 | 0.4 | La planta general y algunos croquis de apoyo muestran dimensiones transversales distintas. Se usan el contorno de cimentación y los centros de pilares de la implantación general; sección de viga VC1 400 × 400 mm y vuelo a 1050 mm del eje según detalle. / La capa de mortero sobre la losa no tiene una referencia vertical inequívoca; no se duplica una capa independiente en esa losa.
Cimentación y plataforma del módulo MV-CONTAINER · pilar KZ1 03 | Parcela industrial Jinhong | Cimentación industrial | Cimentaciones de equipos y pedestales del fabricante · revisión recibida 04/09/2026 | 0.450754 | 0.450753 | 1.1 | 2.08 | 0.176 | process_plant | Zona de separación de aire | {"name":"Hormigón armado · clase pendiente de confirmar","status":"Clase no confirmada en la hoja de equipo","source":"Geometría de cimentación del fabricante; no se extrapola HA-30 de la nota de pedestales."} | {"documented":[{"label":"Extensión local X","value":0.4,"unit":"m","source":"5599/559F, 1DB82, 1DE55","status":"derivada del contorno CAD"},{"label":"Extensión local Y","value":0.4,"unit":"m","source":"5599/559F, 1DB82, 1DE55","status":"derivada del contorno CAD"},{"label":"Cota inferior relativa adoptada","value":0,"unit":"m","source":"16–16","status":"interpretación con conflicto conservado"},{"label":"Cota superior relativa adoptada","value":1.1,"unit":"m","source":"16–16","status":"documentada / separación por material"}],"geometry":[{"label":"Extensión de la malla en X","value":0.45075400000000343,"unit":"m","source":"Geometría releída del IFC; datum absoluto de proceso provisional","status":"derivado"},{"label":"Extensión de la malla en Y","value":0.45075299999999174,"unit":"m","source":"Geometría releída del IFC; datum absoluto de proceso provisional","status":"derivado"},{"label":"Extensión de la malla en Z","value":1.1,"unit":"m","source":"Geometría releída del IFC; datum absoluto de proceso provisional","status":"derivado"},{"label":"Cota inferior de visualización","value":286.1,"unit":"m","source":"Geometría releída del IFC; datum absoluto de proceso provisional","status":"derivado"},{"label":"Cota superior de visualización","value":287.2,"unit":"m","source":"Geometría releída del IFC; datum absoluto de proceso provisional","status":"derivado"}]} | {"documentId":"LHD2609-JG00100-20260904","title":"Cimentaciones de equipos y pedestales del fabricante · revisión recibida 04/09/2026","date":"2026-09-04","sheet":"16–16","fileName":"LHD2609-JG00100_20260904.dwg","revisionCaveat":"Fecha de revisión tomada del nombre recibido; cajetines internos mantienen 02/07/2026 y algunos textos de plantilla.","sourceFileSha256":"b42eb027b7bc0b14c38d1d13514f4899b58a732aa8d0ba2ccf10fa2fc3192890"} | provisional | ["La planta general y algunos croquis de apoyo muestran dimensiones transversales distintas. Se usan el contorno de cimentación y los centros de pilares de la implantación general; sección de viga VC1 400 × 400 mm y vuelo a 1050 mm del eje según detalle.","La capa de mortero sobre la losa no tiene una referencia vertical inequívoca; no se duplica una capa independiente en esa losa."] | {"Cota inferior relativa (m)":0,"Cota superior relativa (m)":1.1,"Cero absoluto de visualización (m)":286.1,"Estado del cero absoluto":"Provisional","Criterio":"Las cotas relativas proceden del dibujo; la equivalencia absoluta no está confirmada."} | {"boundingBoxM":{"min":[50.233092,80.747285,1.1],"max":[50.683846,81.198038,2.2]},"extentsM":[0.450754,0.450753,1.1],"meshSurfaceM2":2.079998,"meshVolumeM3":0.176,"closedSolid":true,"basis":"Magnitudes de las mallas representadas, no cantidades certificadas de obra, compra o fabricación. Las partes pueden compartir superficies; no se suman como un despiece de materiales."} | {"profileId":"concrete_reinforced","name":"Hormigón armado · gris natural","materialName":"Hormigón armado · clase pendiente de confirmar","physicalMaterialStatus":"Clase no confirmada en la hoja de equipo","physicalMaterialSource":"Geometría de cimentación del fabricante; no se extrapola HA-30 de la nota de pedestales.","appearanceStatus":"criterio_visual","appearanceBasis":"Interpretación visual del material documental; el acabado, tono y parámetros PBR no son una especificación contractual.","note":"La apariencia gráfica no modifica ni confirma la especificación física del material."} | {"elementId":"found_0904_8421c28e52c7e3","ifcGuid":"3obX_aNVvVufcengNGqGmy","ifcClass":"IfcFooting","buildingId":"process_plant","buildingName":"Zona de separación de aire","sourceDocumentId":"LHD2609-JG00100-20260904","sourceRepresentationKind":"foundation"} | {"layerId":"foundations","layerName":"Cimentaciones","role":"Cimentación industrial","basis":"Clasificación por función del elemento; no modifica las especificaciones documentales."} | {"profileId":"concrete_reinforced","name":"Hormigón armado · gris natural","status":"criterio_visual","basis":"Interpretación visual del material documental; el acabado, tono y parámetros PBR no son una especificación contractual.","physicalMaterialUnchanged":true} | 0.176 | Hormigón armado · clase pendiente de confirmar | Hormigón armado · gris natural | found_0904_8421c28e52c7e3 | Geometría de cimentación del fabricante; no se extrapola HA-30 de la nota de pedestales. | Clase no confirmada en la hoja de equipo | concrete_reinforced | [0.666667,0.662745,0.619608] | 0.96 | Zona de separación de aire; BIM · Cimentaciones | 0.450754 | 0.450753 | 1.1 | 286.1 | 287.2 | F-MV-CONTAINER | ["MV-CONTAINER"] | [] | 16–16 | ["5599/559F","1DB82","1DE55"] | F-MV-CONTAINER/Cimentación y plataforma del módulo MV-CONTAINER · pilar KZ1 03 | foundation | Geometría de fabricante; implantación absoluta provisional | MV-CONTAINER | Cimentaciones de equipos y pedestales del fabricante · revisión recibida 04/09/2026 | 5599/559F, 1DB82, 1DE55 | 0 | 1.1 | 0.16 | Cotas relativas del dibujo. La equivalencia con un datum absoluto está pendiente. | Z del modelo = cota relativa + 1,10 m. Correspondencia provisional con 286,10 m; no es cota de obra confirmada. | Sección y contornos del fabricante; incidencias conservadas | 0.4 | 0.4 | La planta general y algunos croquis de apoyo muestran dimensiones transversales distintas. Se usan el contorno de cimentación y los centros de pilares de la implantación general; sección de viga VC1 400 × 400 mm y vuelo a 1050 mm del eje según detalle. / La capa de mortero sobre la losa no tiene una referencia vertical inequívoca; no se duplica una capa independiente en esa losa.
Cimentación y plataforma del módulo MV-CONTAINER · pilar KZ1 04 | Parcela industrial Jinhong | Cimentación industrial | Cimentaciones de equipos y pedestales del fabricante · revisión recibida 04/09/2026 | 0.450753 | 0.450754 | 1.1 | 2.08 | 0.176 | process_plant | Zona de separación de aire | {"name":"Hormigón armado · clase pendiente de confirmar","status":"Clase no confirmada en la hoja de equipo","source":"Geometría de cimentación del fabricante; no se extrapola HA-30 de la nota de pedestales."} | {"documented":[{"label":"Extensión local X","value":0.4,"unit":"m","source":"5599/559F, 1DB82, 1DE55","status":"derivada del contorno CAD"},{"label":"Extensión local Y","value":0.4,"unit":"m","source":"5599/559F, 1DB82, 1DE55","status":"derivada del contorno CAD"},{"label":"Cota inferior relativa adoptada","value":0,"unit":"m","source":"16–16","status":"interpretación con conflicto conservado"},{"label":"Cota superior relativa adoptada","value":1.1,"unit":"m","source":"16–16","status":"documentada / separación por material"}],"geometry":[{"label":"Extensión de la malla en X","value":0.45075300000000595,"unit":"m","source":"Geometría releída del IFC; datum absoluto de proceso provisional","status":"derivado"},{"label":"Extensión de la malla en Y","value":0.4507539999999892,"unit":"m","source":"Geometría releída del IFC; datum absoluto de proceso provisional","status":"derivado"},{"label":"Extensión de la malla en Z","value":1.1,"unit":"m","source":"Geometría releída del IFC; datum absoluto de proceso provisional","status":"derivado"},{"label":"Cota inferior de visualización","value":286.1,"unit":"m","source":"Geometría releída del IFC; datum absoluto de proceso provisional","status":"derivado"},{"label":"Cota superior de visualización","value":287.2,"unit":"m","source":"Geometría releída del IFC; datum absoluto de proceso provisional","status":"derivado"}]} | {"documentId":"LHD2609-JG00100-20260904","title":"Cimentaciones de equipos y pedestales del fabricante · revisión recibida 04/09/2026","date":"2026-09-04","sheet":"16–16","fileName":"LHD2609-JG00100_20260904.dwg","revisionCaveat":"Fecha de revisión tomada del nombre recibido; cajetines internos mantienen 02/07/2026 y algunos textos de plantilla.","sourceFileSha256":"b42eb027b7bc0b14c38d1d13514f4899b58a732aa8d0ba2ccf10fa2fc3192890"} | provisional | ["La planta general y algunos croquis de apoyo muestran dimensiones transversales distintas. Se usan el contorno de cimentación y los centros de pilares de la implantación general; sección de viga VC1 400 × 400 mm y vuelo a 1050 mm del eje según detalle.","La capa de mortero sobre la losa no tiene una referencia vertical inequívoca; no se duplica una capa independiente en esa losa."] | {"Cota inferior relativa (m)":0,"Cota superior relativa (m)":1.1,"Cero absoluto de visualización (m)":286.1,"Estado del cero absoluto":"Provisional","Criterio":"Las cotas relativas proceden del dibujo; la equivalencia absoluta no está confirmada."} | {"boundingBoxM":{"min":[53.576145,80.287664,1.1],"max":[54.026898,80.738418,2.2]},"extentsM":[0.450753,0.450754,1.1],"meshSurfaceM2":2.079999,"meshVolumeM3":0.176,"closedSolid":true,"basis":"Magnitudes de las mallas representadas, no cantidades certificadas de obra, compra o fabricación. Las partes pueden compartir superficies; no se suman como un despiece de materiales."} | {"profileId":"concrete_reinforced","name":"Hormigón armado · gris natural","materialName":"Hormigón armado · clase pendiente de confirmar","physicalMaterialStatus":"Clase no confirmada en la hoja de equipo","physicalMaterialSource":"Geometría de cimentación del fabricante; no se extrapola HA-30 de la nota de pedestales.","appearanceStatus":"criterio_visual","appearanceBasis":"Interpretación visual del material documental; el acabado, tono y parámetros PBR no son una especificación contractual.","note":"La apariencia gráfica no modifica ni confirma la especificación física del material."} | {"elementId":"found_0904_ea9ba8ece9deba","ifcGuid":"28CGsdmGDH0BGq2zn2xaGT","ifcClass":"IfcFooting","buildingId":"process_plant","buildingName":"Zona de separación de aire","sourceDocumentId":"LHD2609-JG00100-20260904","sourceRepresentationKind":"foundation"} | {"layerId":"foundations","layerName":"Cimentaciones","role":"Cimentación industrial","basis":"Clasificación por función del elemento; no modifica las especificaciones documentales."} | {"profileId":"concrete_reinforced","name":"Hormigón armado · gris natural","status":"criterio_visual","basis":"Interpretación visual del material documental; el acabado, tono y parámetros PBR no son una especificación contractual.","physicalMaterialUnchanged":true} | 0.176 | Hormigón armado · clase pendiente de confirmar | Hormigón armado · gris natural | found_0904_ea9ba8ece9deba | Geometría de cimentación del fabricante; no se extrapola HA-30 de la nota de pedestales. | Clase no confirmada en la hoja de equipo | concrete_reinforced | [0.666667,0.662745,0.619608] | 0.96 | Zona de separación de aire; BIM · Cimentaciones | 0.450753 | 0.450754 | 1.1 | 286.1 | 287.2 | F-MV-CONTAINER | ["MV-CONTAINER"] | [] | 16–16 | ["5599/559F","1DB82","1DE55"] | F-MV-CONTAINER/Cimentación y plataforma del módulo MV-CONTAINER · pilar KZ1 04 | foundation | Geometría de fabricante; implantación absoluta provisional | MV-CONTAINER | Cimentaciones de equipos y pedestales del fabricante · revisión recibida 04/09/2026 | 5599/559F, 1DB82, 1DE55 | 0 | 1.1 | 0.16 | Cotas relativas del dibujo. La equivalencia con un datum absoluto está pendiente. | Z del modelo = cota relativa + 1,10 m. Correspondencia provisional con 286,10 m; no es cota de obra confirmada. | Sección y contornos del fabricante; incidencias conservadas | 0.4 | 0.4 | La planta general y algunos croquis de apoyo muestran dimensiones transversales distintas. Se usan el contorno de cimentación y los centros de pilares de la implantación general; sección de viga VC1 400 × 400 mm y vuelo a 1050 mm del eje según detalle. / La capa de mortero sobre la losa no tiene una referencia vertical inequívoca; no se duplica una capa independiente en esa losa.
Cimentación y plataforma del módulo MV-CONTAINER · pilar KZ1 05 | Parcela industrial Jinhong | Cimentación industrial | Cimentaciones de equipos y pedestales del fabricante · revisión recibida 04/09/2026 | 0.450753 | 0.450754 | 1.1 | 2.08 | 0.176 | process_plant | Zona de separación de aire | {"name":"Hormigón armado · clase pendiente de confirmar","status":"Clase no confirmada en la hoja de equipo","source":"Geometría de cimentación del fabricante; no se extrapola HA-30 de la nota de pedestales."} | {"documented":[{"label":"Extensión local X","value":0.4,"unit":"m","source":"5599/559F, 1DB82, 1DE55","status":"derivada del contorno CAD"},{"label":"Extensión local Y","value":0.4,"unit":"m","source":"5599/559F, 1DB82, 1DE55","status":"derivada del contorno CAD"},{"label":"Cota inferior relativa adoptada","value":0,"unit":"m","source":"16–16","status":"interpretación con conflicto conservado"},{"label":"Cota superior relativa adoptada","value":1.1,"unit":"m","source":"16–16","status":"documentada / separación por material"}],"geometry":[{"label":"Extensión de la malla en X","value":0.45075299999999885,"unit":"m","source":"Geometría releída del IFC; datum absoluto de proceso provisional","status":"derivado"},{"label":"Extensión de la malla en Y","value":0.45075400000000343,"unit":"m","source":"Geometría releída del IFC; datum absoluto de proceso provisional","status":"derivado"},{"label":"Extensión de la malla en Z","value":1.1,"unit":"m","source":"Geometría releída del IFC; datum absoluto de proceso provisional","status":"derivado"},{"label":"Cota inferior de visualización","value":286.1,"unit":"m","source":"Geometría releída del IFC; datum absoluto de proceso provisional","status":"derivado"},{"label":"Cota superior de visualización","value":287.2,"unit":"m","source":"Geometría releída del IFC; datum absoluto de proceso provisional","status":"derivado"}]} | {"documentId":"LHD2609-JG00100-20260904","title":"Cimentaciones de equipos y pedestales del fabricante · revisión recibida 04/09/2026","date":"2026-09-04","sheet":"16–16","fileName":"LHD2609-JG00100_20260904.dwg","revisionCaveat":"Fecha de revisión tomada del nombre recibido; cajetines internos mantienen 02/07/2026 y algunos textos de plantilla.","sourceFileSha256":"b42eb027b7bc0b14c38d1d13514f4899b58a732aa8d0ba2ccf10fa2fc3192890"} | provisional | ["La planta general y algunos croquis de apoyo muestran dimensiones transversales distintas. Se usan el contorno de cimentación y los centros de pilares de la implantación general; sección de viga VC1 400 × 400 mm y vuelo a 1050 mm del eje según detalle.","La capa de mortero sobre la losa no tiene una referencia vertical inequívoca; no se duplica una capa independiente en esa losa."] | {"Cota inferior relativa (m)":0,"Cota superior relativa (m)":1.1,"Cero absoluto de visualización (m)":286.1,"Estado del cero absoluto":"Provisional","Criterio":"Las cotas relativas proceden del dibujo; la equivalencia absoluta no está confirmada."} | {"boundingBoxM":{"min":[47.290851,84.129549,1.1],"max":[47.741604,84.580303,2.2]},"extentsM":[0.450753,0.450754,1.1],"meshSurfaceM2":2.079999,"meshVolumeM3":0.176,"closedSolid":true,"basis":"Magnitudes de las mallas representadas, no cantidades certificadas de obra, compra o fabricación. Las partes pueden compartir superficies; no se suman como un despiece de materiales."} | {"profileId":"concrete_reinforced","name":"Hormigón armado · gris natural","materialName":"Hormigón armado · clase pendiente de confirmar","physicalMaterialStatus":"Clase no confirmada en la hoja de equipo","physicalMaterialSource":"Geometría de cimentación del fabricante; no se extrapola HA-30 de la nota de pedestales.","appearanceStatus":"criterio_visual","appearanceBasis":"Interpretación visual del material documental; el acabado, tono y parámetros PBR no son una especificación contractual.","note":"La apariencia gráfica no modifica ni confirma la especificación física del material."} | {"elementId":"found_0904_499ff58d04697b","ifcGuid":"2GlNTAXrTSdf91Cy$FTFfS","ifcClass":"IfcFooting","buildingId":"process_plant","buildingName":"Zona de separación de aire","sourceDocumentId":"LHD2609-JG00100-20260904","sourceRepresentationKind":"foundation"} | {"layerId":"foundations","layerName":"Cimentaciones","role":"Cimentación industrial","basis":"Clasificación por función del elemento; no modifica las especificaciones documentales."} | {"profileId":"concrete_reinforced","name":"Hormigón armado · gris natural","status":"criterio_visual","basis":"Interpretación visual del material documental; el acabado, tono y parámetros PBR no son una especificación contractual.","physicalMaterialUnchanged":true} | 0.176 | Hormigón armado · clase pendiente de confirmar | Hormigón armado · gris natural | found_0904_499ff58d04697b | Geometría de cimentación del fabricante; no se extrapola HA-30 de la nota de pedestales. | Clase no confirmada en la hoja de equipo | concrete_reinforced | [0.666667,0.662745,0.619608] | 0.96 | Zona de separación de aire; BIM · Cimentaciones | 0.450753 | 0.450754 | 1.1 | 286.1 | 287.2 | F-MV-CONTAINER | ["MV-CONTAINER"] | [] | 16–16 | ["5599/559F","1DB82","1DE55"] | F-MV-CONTAINER/Cimentación y plataforma del módulo MV-CONTAINER · pilar KZ1 05 | foundation | Geometría de fabricante; implantación absoluta provisional | MV-CONTAINER | Cimentaciones de equipos y pedestales del fabricante · revisión recibida 04/09/2026 | 5599/559F, 1DB82, 1DE55 | 0 | 1.1 | 0.16 | Cotas relativas del dibujo. La equivalencia con un datum absoluto está pendiente. | Z del modelo = cota relativa + 1,10 m. Correspondencia provisional con 286,10 m; no es cota de obra confirmada. | Sección y contornos del fabricante; incidencias conservadas | 0.4 | 0.4 | La planta general y algunos croquis de apoyo muestran dimensiones transversales distintas. Se usan el contorno de cimentación y los centros de pilares de la implantación general; sección de viga VC1 400 × 400 mm y vuelo a 1050 mm del eje según detalle. / La capa de mortero sobre la losa no tiene una referencia vertical inequívoca; no se duplica una capa independiente en esa losa.
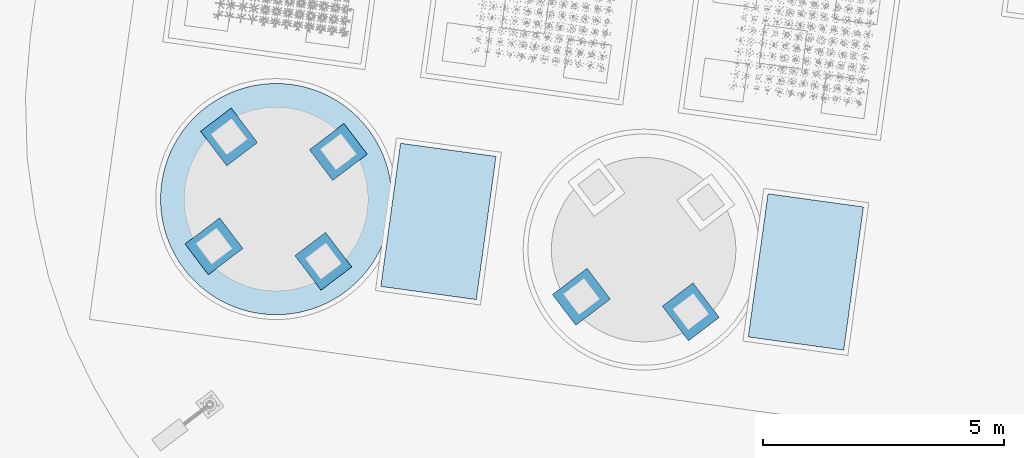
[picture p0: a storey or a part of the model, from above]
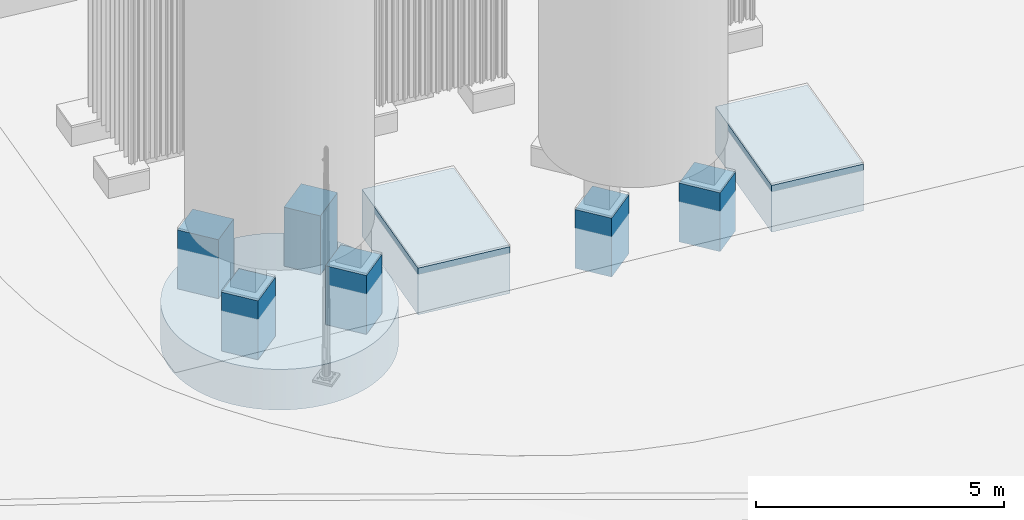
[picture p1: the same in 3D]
Properties of the parts of a building model (IFC4), part 78 of 134

# IfcFooting (214)
Name | In | Description = category = Categoria = Funcion | Document | ExtensionX (m) | ExtensionY (m) | ExtensionZ (m) | SuperficieDeLaMalla (m2) | VolumenGeometrico (m3) | buildingId | buildingName | material | dimensions | JH_InformacionBIM, source = DocumentoFuente | JH_InformacionBIM, status = EstadoDeInformacion | issues = IncidenciasPendientes | positioning = PosicionYEstado | geometryMetrics | materialAppearance | visualizationIdentity | classification | appearance | Volumen geométrico (m³) | JH_Trazabilidad, Material = name | Acabado de visualización = Acabado | Identificador | JH_EvidenciaDeMaterial, source | JH_EvidenciaDeMaterial, status | Perfil | ColorRGB | Rugosidad | Group | Extensión de la malla en X (m) | Extensión de la malla en Y (m) | Extensión de la malla en Z (m) = Espesor o altura real de sección (m) | Cota inferior de visualización (m) | Cota superior de visualización (m) | assemblyId = Conjunto de cimentación | equipmentIds | supportPositionIds | sectionRef = Sección de referencia | sourceCadHandles | stableElementKey | representationKind | geometryStatus | Equipos asociados | Documento de origen | Identificadores CAD de referencia | Cota inferior relativa (m) = Cota inferior relativa adoptada (m) | Cota superior relativa (m) = Cota superior relativa adoptada (m) | Área de planta (m²) | Referencia vertical | Implantación para visualización | Estado de la geometría | Extensión local X (m) | Extensión local Y (m) | Incidencias de origen
Cimentación y plataforma del módulo MV-CONTAINER · pilar KZ1 06 | Parcela industrial Jinhong | Cimentación industrial | Cimentaciones de equipos y pedestales del fabricante · revisión recibida 04/09/2026 | 0.450754 | 0.450754 | 1.1 | 2.08 | 0.176 | process_plant | Zona de separación de aire | {"name":"Hormigón armado · clase pendiente de confirmar","status":"Clase no confirmada en la hoja de equipo","source":"Geometría de cimentación del fabricante; no se extrapola HA-30 de la nota de pedestales."} | {"documented":[{"label":"Extensión local X","value":0.4,"unit":"m","source":"5599/559F, 1DB82, 1DE55","status":"derivada del contorno CAD"},{"label":"Extensión local Y","value":0.4,"unit":"m","source":"5599/559F, 1DB82, 1DE55","status":"derivada del contorno CAD"},{"label":"Cota inferior relativa adoptada","value":0,"unit":"m","source":"16–16","status":"interpretación con conflicto conservado"},{"label":"Cota superior relativa adoptada","value":1.1,"unit":"m","source":"16–16","status":"documentada / separación por material"}],"geometry":[{"label":"Extensión de la malla en X","value":0.4507539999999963,"unit":"m","source":"Geometría releída del IFC; datum absoluto de proceso provisional","status":"derivado"},{"label":"Extensión de la malla en Y","value":0.45075400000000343,"unit":"m","source":"Geometría releída del IFC; datum absoluto de proceso provisional","status":"derivado"},{"label":"Extensión de la malla en Z","value":1.1,"unit":"m","source":"Geometría releída del IFC; datum absoluto de proceso provisional","status":"derivado"},{"label":"Cota inferior de visualización","value":286.1,"unit":"m","source":"Geometría releída del IFC; datum absoluto de proceso provisional","status":"derivado"},{"label":"Cota superior de visualización","value":287.2,"unit":"m","source":"Geometría releída del IFC; datum absoluto de proceso provisional","status":"derivado"}]} | {"documentId":"LHD2609-JG00100-20260904","title":"Cimentaciones de equipos y pedestales del fabricante · revisión recibida 04/09/2026","date":"2026-09-04","sheet":"16–16","fileName":"LHD2609-JG00100_20260904.dwg","revisionCaveat":"Fecha de revisión tomada del nombre recibido; cajetines internos mantienen 02/07/2026 y algunos textos de plantilla.","sourceFileSha256":"b42eb027b7bc0b14c38d1d13514f4899b58a732aa8d0ba2ccf10fa2fc3192890"} | provisional | ["La planta general y algunos croquis de apoyo muestran dimensiones transversales distintas. Se usan el contorno de cimentación y los centros de pilares de la implantación general; sección de viga VC1 400 × 400 mm y vuelo a 1050 mm del eje según detalle.","La capa de mortero sobre la losa no tiene una referencia vertical inequívoca; no se duplica una capa independiente en esa losa."] | {"Cota inferior relativa (m)":0,"Cota superior relativa (m)":1.1,"Cero absoluto de visualización (m)":286.1,"Estado del cero absoluto":"Provisional","Criterio":"Las cotas relativas proceden del dibujo; la equivalencia absoluta no está confirmada."} | {"boundingBoxM":{"min":[53.977946,83.210173,1.1],"max":[54.4287,83.660927,2.2]},"extentsM":[0.450754,0.450754,1.1],"meshSurfaceM2":2.08,"meshVolumeM3":0.176,"closedSolid":true,"basis":"Magnitudes de las mallas representadas, no cantidades certificadas de obra, compra o fabricación. Las partes pueden compartir superficies; no se suman como un despiece de materiales."} | {"profileId":"concrete_reinforced","name":"Hormigón armado · gris natural","materialName":"Hormigón armado · clase pendiente de confirmar","physicalMaterialStatus":"Clase no confirmada en la hoja de equipo","physicalMaterialSource":"Geometría de cimentación del fabricante; no se extrapola HA-30 de la nota de pedestales.","appearanceStatus":"criterio_visual","appearanceBasis":"Interpretación visual del material documental; el acabado, tono y parámetros PBR no son una especificación contractual.","note":"La apariencia gráfica no modifica ni confirma la especificación física del material."} | {"elementId":"found_0904_62918767cf4ba3","ifcGuid":"0z8KOTzGTL0hiHTUJ5xSdN","ifcClass":"IfcFooting","buildingId":"process_plant","buildingName":"Zona de separación de aire","sourceDocumentId":"LHD2609-JG00100-20260904","sourceRepresentationKind":"foundation"} | {"layerId":"foundations","layerName":"Cimentaciones","role":"Cimentación industrial","basis":"Clasificación por función del elemento; no modifica las especificaciones documentales."} | {"profileId":"concrete_reinforced","name":"Hormigón armado · gris natural","status":"criterio_visual","basis":"Interpretación visual del material documental; el acabado, tono y parámetros PBR no son una especificación contractual.","physicalMaterialUnchanged":true} | 0.176 | Hormigón armado · clase pendiente de confirmar | Hormigón armado · gris natural | found_0904_62918767cf4ba3 | Geometría de cimentación del fabricante; no se extrapola HA-30 de la nota de pedestales. | Clase no confirmada en la hoja de equipo | concrete_reinforced | [0.666667,0.662745,0.619608] | 0.96 | Zona de separación de aire; BIM · Cimentaciones | 0.450754 | 0.450754 | 1.1 | 286.1 | 287.2 | F-MV-CONTAINER | ["MV-CONTAINER"] | [] | 16–16 | ["5599/559F","1DB82","1DE55"] | F-MV-CONTAINER/Cimentación y plataforma del módulo MV-CONTAINER · pilar KZ1 06 | foundation | Geometría de fabricante; implantación absoluta provisional | MV-CONTAINER | Cimentaciones de equipos y pedestales del fabricante · revisión recibida 04/09/2026 | 5599/559F, 1DB82, 1DE55 | 0 | 1.1 | 0.16 | Cotas relativas del dibujo. La equivalencia con un datum absoluto está pendiente. | Z del modelo = cota relativa + 1,10 m. Correspondencia provisional con 286,10 m; no es cota de obra confirmada. | Sección y contornos del fabricante; incidencias conservadas | 0.4 | 0.4 | La planta general y algunos croquis de apoyo muestran dimensiones transversales distintas. Se usan el contorno de cimentación y los centros de pilares de la implantación general; sección de viga VC1 400 × 400 mm y vuelo a 1050 mm del eje según detalle. / La capa de mortero sobre la losa no tiene una referencia vertical inequívoca; no se duplica una capa independiente en esa losa.
Cimentación de soporte de tuberías C01 · cuerpo de hormigón | Parcela industrial Jinhong | Cimentación industrial | Cimentaciones de equipos y pedestales del fabricante · revisión recibida 04/09/2026 | 1.12689 | 1.12689 | 0.4 | 3.6 | 0.4 | process_plant | Zona de separación de aire | {"name":"Hormigón HA-30","status":"documentado","source":"Nota general de pedestales 2CED5"} | {"documented":[{"label":"Extensión local X","value":1.0,"unit":"m","source":"2CC56, 2CC2F, 2CCC9, 2CC64, 2CC21, 2CC28, 2CCA9, 2CEA7, 2CE82","status":"derivada del contorno CAD"},{"label":"Extensión local Y","value":1.0,"unit":"m","source":"2CC56, 2CC2F, 2CCC9, 2CC64, 2CC21, 2CC28, 2CCA9, 2CEA7, 2CE82","status":"derivada del contorno CAD"},{"label":"Cota inferior relativa adoptada","value":-1.0,"unit":"m","source":"ZD1 / DZ-1","status":"documentada"},{"label":"Cota superior relativa adoptada","value":-0.6,"unit":"m","source":"ZD1 / DZ-1","status":"documentada / separación por material"}],"geometry":[{"label":"Extensión de la malla en X","value":1.1268850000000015,"unit":"m","source":"Geometría releída del IFC; datum absoluto de proceso provisional","status":"derivado"},{"label":"Extensión de la malla en Y","value":1.1268850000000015,"unit":"m","source":"Geometría releída del IFC; datum absoluto de proceso provisional","status":"derivado"},{"label":"Extensión de la malla en Z","value":0.4,"unit":"m","source":"Geometría releída del IFC; datum absoluto de proceso provisional","status":"derivado"},{"label":"Cota inferior de visualización","value":285.1,"unit":"m","source":"Geometría releída del IFC; datum absoluto de proceso provisional","status":"derivado"},{"label":"Cota superior de visualización","value":285.5,"unit":"m","source":"Geometría releída del IFC; datum absoluto de proceso provisional","status":"derivado"}]} | {"documentId":"LHD2609-JG00100-20260904","title":"Cimentaciones de equipos y pedestales del fabricante · revisión recibida 04/09/2026","date":"2026-09-04","sheet":"ZD1 / DZ-1","fileName":"LHD2609-JG00100_20260904.dwg","revisionCaveat":"Fecha de revisión tomada del nombre recibido; cajetines internos mantienen 02/07/2026 y algunos textos de plantilla.","sourceFileSha256":"b42eb027b7bc0b14c38d1d13514f4899b58a732aa8d0ba2ccf10fa2fc3192890"} | provisional | [] | {"Cota inferior relativa (m)":-1.0,"Cota superior relativa (m)":-0.6,"Cero absoluto de visualización (m)":286.1,"Estado del cero absoluto":"Provisional","Criterio":"Las cotas relativas proceden del dibujo; la equivalencia absoluta no está confirmada."} | {"boundingBoxM":{"min":[47.806885,78.80367,0.1],"max":[48.93377,79.930555,0.5]},"extentsM":[1.126885,1.126885,0.4],"meshSurfaceM2":3.600001,"meshVolumeM3":0.4,"closedSolid":true,"basis":"Magnitudes de las mallas representadas, no cantidades certificadas de obra, compra o fabricación. Las partes pueden compartir superficies; no se suman como un despiece de materiales."} | {"profileId":"concrete_ha30","name":"Hormigón HA-30","materialName":"Hormigón HA-30","physicalMaterialStatus":"documentado","physicalMaterialSource":"Nota general de pedestales 2CED5","appearanceStatus":"criterio_visual","appearanceBasis":"Interpretación visual del material documental; el acabado, tono y parámetros PBR no son una especificación contractual.","note":"La apariencia gráfica no modifica ni confirma la especificación física del material."} | {"elementId":"found_0904_9363987a66a96d","ifcGuid":"1$qXAzs99VUR0T5pGqmQg7","ifcClass":"IfcFooting","buildingId":"process_plant","buildingName":"Zona de separación de aire","sourceDocumentId":"LHD2609-JG00100-20260904","sourceRepresentationKind":"foundation"} | {"layerId":"foundations","layerName":"Cimentaciones","role":"Cimentación industrial","basis":"Clasificación por función del elemento; no modifica las especificaciones documentales."} | {"profileId":"concrete_ha30","name":"Hormigón HA-30","status":"criterio_visual","basis":"Interpretación visual del material documental; el acabado, tono y parámetros PBR no son una especificación contractual.","physicalMaterialUnchanged":true} | 0.4 | Hormigón HA-30 | Hormigón HA-30 | found_0904_9363987a66a96d | Nota general de pedestales 2CED5 | documentado | concrete_ha30 | [0.658824,0.658824,0.623529] | 0.94 | Zona de separación de aire; BIM · Cimentaciones | 1.12689 | 1.12689 | 0.4 | 285.1 | 285.5 | SUP-C01 | [] | ["C01"] | ZD1 / DZ-1 | ["2CC56","2CC2F","2CCC9","2CC64","2CC21","2CC28","2CCA9","2CEA7","2CE82"] | SUP-C01/Cimentación de soporte de tuberías C01 · cuerpo de hormigón | foundation | Geometría de fabricante; implantación absoluta provisional |  | Cimentaciones de equipos y pedestales del fabricante · revisión recibida 04/09/2026 | 2CC56, 2CC2F, 2CCC9, 2CC64, 2CC21, 2CC28, 2CCA9, 2CEA7, 2CE82 | -1 | -0.6 | 1 | Cotas relativas del dibujo. La equivalencia con un datum absoluto está pendiente. | Z del modelo = cota relativa + 1,10 m. Correspondencia provisional con 286,10 m; no es cota de obra confirmada. | Contornos y sección documentados por el fabricante | 1 | 1 | Material: Hormigón HA-30
Cimentación de soporte de tuberías C01 · pedestal de hormigón | Parcela industrial Jinhong | Cimentación industrial | Cimentaciones de equipos y pedestales del fabricante · revisión recibida 04/09/2026 | 0.507098 | 0.507098 | 0.8 | 1.845 | 0.162 | process_plant | Zona de separación de aire | {"name":"Hormigón HA-30","status":"documentado","source":"Nota general de pedestales 2CED5"} | {"documented":[{"label":"Extensión local X","value":0.45,"unit":"m","source":"2CC56, 2CC2F, 2CCC9, 2CC64, 2CC21, 2CC28, 2CCA9, 2CEA7, 2CE82","status":"derivada del contorno CAD"},{"label":"Extensión local Y","value":0.45,"unit":"m","source":"2CC56, 2CC2F, 2CCC9, 2CC64, 2CC21, 2CC28, 2CCA9, 2CEA7, 2CE82","status":"derivada del contorno CAD"},{"label":"Cota inferior relativa adoptada","value":-0.6,"unit":"m","source":"ZD1 / DZ-1","status":"documentada"},{"label":"Cota superior relativa adoptada","value":0.2,"unit":"m","source":"ZD1 / DZ-1","status":"documentada / separación por material"}],"geometry":[{"label":"Extensión de la malla en X","value":0.5070980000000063,"unit":"m","source":"Geometría releída del IFC; datum absoluto de proceso provisional","status":"derivado"},{"label":"Extensión de la malla en Y","value":0.5070979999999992,"unit":"m","source":"Geometría releída del IFC; datum absoluto de proceso provisional","status":"derivado"},{"label":"Extensión de la malla en Z","value":0.8,"unit":"m","source":"Geometría releída del IFC; datum absoluto de proceso provisional","status":"derivado"},{"label":"Cota inferior de visualización","value":285.5,"unit":"m","source":"Geometría releída del IFC; datum absoluto de proceso provisional","status":"derivado"},{"label":"Cota superior de visualización","value":286.3,"unit":"m","source":"Geometría releída del IFC; datum absoluto de proceso provisional","status":"derivado"}]} | {"documentId":"LHD2609-JG00100-20260904","title":"Cimentaciones de equipos y pedestales del fabricante · revisión recibida 04/09/2026","date":"2026-09-04","sheet":"ZD1 / DZ-1","fileName":"LHD2609-JG00100_20260904.dwg","revisionCaveat":"Fecha de revisión tomada del nombre recibido; cajetines internos mantienen 02/07/2026 y algunos textos de plantilla.","sourceFileSha256":"b42eb027b7bc0b14c38d1d13514f4899b58a732aa8d0ba2ccf10fa2fc3192890"} | provisional | [] | {"Cota inferior relativa (m)":-0.6,"Cota superior relativa (m)":0.2,"Cero absoluto de visualización (m)":286.1,"Estado del cero absoluto":"Provisional","Criterio":"Las cotas relativas proceden del dibujo; la equivalencia absoluta no está confirmada."} | {"boundingBoxM":{"min":[48.116778,79.113563,0.5],"max":[48.623876,79.620661,1.3]},"extentsM":[0.507098,0.507098,0.8],"meshSurfaceM2":1.844998,"meshVolumeM3":0.162,"closedSolid":true,"basis":"Magnitudes de las mallas representadas, no cantidades certificadas de obra, compra o fabricación. Las partes pueden compartir superficies; no se suman como un despiece de materiales."} | {"profileId":"concrete_ha30","name":"Hormigón HA-30","materialName":"Hormigón HA-30","physicalMaterialStatus":"documentado","physicalMaterialSource":"Nota general de pedestales 2CED5","appearanceStatus":"criterio_visual","appearanceBasis":"Interpretación visual del material documental; el acabado, tono y parámetros PBR no son una especificación contractual.","note":"La apariencia gráfica no modifica ni confirma la especificación física del material."} | {"elementId":"found_0904_35f76e4a0cd7d5","ifcGuid":"0prGJ$rcPKn9exs1pIVQHX","ifcClass":"IfcFooting","buildingId":"process_plant","buildingName":"Zona de separación de aire","sourceDocumentId":"LHD2609-JG00100-20260904","sourceRepresentationKind":"foundation"} | {"layerId":"foundations","layerName":"Cimentaciones","role":"Cimentación industrial","basis":"Clasificación por función del elemento; no modifica las especificaciones documentales."} | {"profileId":"concrete_ha30","name":"Hormigón HA-30","status":"criterio_visual","basis":"Interpretación visual del material documental; el acabado, tono y parámetros PBR no son una especificación contractual.","physicalMaterialUnchanged":true} | 0.162 | Hormigón HA-30 | Hormigón HA-30 | found_0904_35f76e4a0cd7d5 | Nota general de pedestales 2CED5 | documentado | concrete_ha30 | [0.658824,0.658824,0.623529] | 0.94 | Zona de separación de aire; BIM · Cimentaciones | 0.507098 | 0.507098 | 0.8 | 285.5 | 286.3 | SUP-C01 | [] | ["C01"] | ZD1 / DZ-1 | ["2CC56","2CC2F","2CCC9","2CC64","2CC21","2CC28","2CCA9","2CEA7","2CE82"] | SUP-C01/Cimentación de soporte de tuberías C01 · pedestal de hormigón | foundation | Geometría de fabricante; implantación absoluta provisional |  | Cimentaciones de equipos y pedestales del fabricante · revisión recibida 04/09/2026 | 2CC56, 2CC2F, 2CCC9, 2CC64, 2CC21, 2CC28, 2CCA9, 2CEA7, 2CE82 | -0.6 | 0.2 | 0.2025 | Cotas relativas del dibujo. La equivalencia con un datum absoluto está pendiente. | Z del modelo = cota relativa + 1,10 m. Correspondencia provisional con 286,10 m; no es cota de obra confirmada. | Contornos y sección documentados por el fabricante | 0.45 | 0.45 | Material: Hormigón HA-30
Cimentación de soporte de tuberías C02 · cuerpo de hormigón | Parcela industrial Jinhong | Cimentación industrial | Cimentaciones de equipos y pedestales del fabricante · revisión recibida 04/09/2026 | 1.12688 | 1.12689 | 0.4 | 3.6 | 0.4 | process_plant | Zona de separación de aire | {"name":"Hormigón HA-30","status":"documentado","source":"Nota general de pedestales 2CED5"} | {"documented":[{"label":"Extensión local X","value":1.0,"unit":"m","source":"2CC57, 2CD32, 2CD35, 2CD33, 2CD30, 2CD31, 2CD34, 2CEA8, 2CE83","status":"derivada del contorno CAD"},{"label":"Extensión local Y","value":1.0,"unit":"m","source":"2CC57, 2CD32, 2CD35, 2CD33, 2CD30, 2CD31, 2CD34, 2CEA8, 2CE83","status":"derivada del contorno CAD"},{"label":"Cota inferior relativa adoptada","value":-1.0,"unit":"m","source":"ZD1 / DZ-1","status":"documentada"},{"label":"Cota superior relativa adoptada","value":-0.6,"unit":"m","source":"ZD1 / DZ-1","status":"documentada / separación por material"}],"geometry":[{"label":"Extensión de la malla en X","value":1.1268839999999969,"unit":"m","source":"Geometría releída del IFC; datum absoluto de proceso provisional","status":"derivado"},{"label":"Extensión de la malla en Y","value":1.1268850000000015,"unit":"m","source":"Geometría releída del IFC; datum absoluto de proceso provisional","status":"derivado"},{"label":"Extensión de la malla en Z","value":0.4,"unit":"m","source":"Geometría releída del IFC; datum absoluto de proceso provisional","status":"derivado"},{"label":"Cota inferior de visualización","value":285.1,"unit":"m","source":"Geometría releída del IFC; datum absoluto de proceso provisional","status":"derivado"},{"label":"Cota superior de visualización","value":285.5,"unit":"m","source":"Geometría releída del IFC; datum absoluto de proceso provisional","status":"derivado"}]} | {"documentId":"LHD2609-JG00100-20260904","title":"Cimentaciones de equipos y pedestales del fabricante · revisión recibida 04/09/2026","date":"2026-09-04","sheet":"ZD1 / DZ-1","fileName":"LHD2609-JG00100_20260904.dwg","revisionCaveat":"Fecha de revisión tomada del nombre recibido; cajetines internos mantienen 02/07/2026 y algunos textos de plantilla.","sourceFileSha256":"b42eb027b7bc0b14c38d1d13514f4899b58a732aa8d0ba2ccf10fa2fc3192890"} | provisional | [] | {"Cota inferior relativa (m)":-1.0,"Cota superior relativa (m)":-0.6,"Cero absoluto de visualización (m)":286.1,"Estado del cero absoluto":"Provisional","Criterio":"Las cotas relativas proceden del dibujo; la equivalencia absoluta no está confirmada."} | {"boundingBoxM":{"min":[47.667276,77.788222,0.1],"max":[48.79416,78.915107,0.5]},"extentsM":[1.126884,1.126885,0.4],"meshSurfaceM2":3.599999,"meshVolumeM3":0.4,"closedSolid":true,"basis":"Magnitudes de las mallas representadas, no cantidades certificadas de obra, compra o fabricación. Las partes pueden compartir superficies; no se suman como un despiece de materiales."} | {"profileId":"concrete_ha30","name":"Hormigón HA-30","materialName":"Hormigón HA-30","physicalMaterialStatus":"documentado","physicalMaterialSource":"Nota general de pedestales 2CED5","appearanceStatus":"criterio_visual","appearanceBasis":"Interpretación visual del material documental; el acabado, tono y parámetros PBR no son una especificación contractual.","note":"La apariencia gráfica no modifica ni confirma la especificación física del material."} | {"elementId":"found_0904_d984d364d15d93","ifcGuid":"0tiCXra$1RoOvvI8fq7QLw","ifcClass":"IfcFooting","buildingId":"process_plant","buildingName":"Zona de separación de aire","sourceDocumentId":"LHD2609-JG00100-20260904","sourceRepresentationKind":"foundation"} | {"layerId":"foundations","layerName":"Cimentaciones","role":"Cimentación industrial","basis":"Clasificación por función del elemento; no modifica las especificaciones documentales."} | {"profileId":"concrete_ha30","name":"Hormigón HA-30","status":"criterio_visual","basis":"Interpretación visual del material documental; el acabado, tono y parámetros PBR no son una especificación contractual.","physicalMaterialUnchanged":true} | 0.4 | Hormigón HA-30 | Hormigón HA-30 | found_0904_d984d364d15d93 | Nota general de pedestales 2CED5 | documentado | concrete_ha30 | [0.658824,0.658824,0.623529] | 0.94 | Zona de separación de aire; BIM · Cimentaciones | 1.12688 | 1.12689 | 0.4 | 285.1 | 285.5 | SUP-C02 | [] | ["C02"] | ZD1 / DZ-1 | ["2CC57","2CD32","2CD35","2CD33","2CD30","2CD31","2CD34","2CEA8","2CE83"] | SUP-C02/Cimentación de soporte de tuberías C02 · cuerpo de hormigón | foundation | Geometría de fabricante; implantación absoluta provisional |  | Cimentaciones de equipos y pedestales del fabricante · revisión recibida 04/09/2026 | 2CC57, 2CD32, 2CD35, 2CD33, 2CD30, 2CD31, 2CD34, 2CEA8, 2CE83 | -1 | -0.6 | 1 | Cotas relativas del dibujo. La equivalencia con un datum absoluto está pendiente. | Z del modelo = cota relativa + 1,10 m. Correspondencia provisional con 286,10 m; no es cota de obra confirmada. | Contornos y sección documentados por el fabricante | 1 | 1 | Material: Hormigón HA-30
Cimentación de soporte de tuberías C02 · pedestal de hormigón | Parcela industrial Jinhong | Cimentación industrial | Cimentaciones de equipos y pedestales del fabricante · revisión recibida 04/09/2026 | 0.507098 | 0.507098 | 0.8 | 1.845 | 0.162 | process_plant | Zona de separación de aire | {"name":"Hormigón HA-30","status":"documentado","source":"Nota general de pedestales 2CED5"} | {"documented":[{"label":"Extensión local X","value":0.45,"unit":"m","source":"2CC57, 2CD32, 2CD35, 2CD33, 2CD30, 2CD31, 2CD34, 2CEA8, 2CE83","status":"derivada del contorno CAD"},{"label":"Extensión local Y","value":0.45,"unit":"m","source":"2CC57, 2CD32, 2CD35, 2CD33, 2CD30, 2CD31, 2CD34, 2CEA8, 2CE83","status":"derivada del contorno CAD"},{"label":"Cota inferior relativa adoptada","value":-0.6,"unit":"m","source":"ZD1 / DZ-1","status":"documentada"},{"label":"Cota superior relativa adoptada","value":0.2,"unit":"m","source":"ZD1 / DZ-1","status":"documentada / separación por material"}],"geometry":[{"label":"Extensión de la malla en X","value":0.5070979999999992,"unit":"m","source":"Geometría releída del IFC; datum absoluto de proceso provisional","status":"derivado"},{"label":"Extensión de la malla en Y","value":0.5070979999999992,"unit":"m","source":"Geometría releída del IFC; datum absoluto de proceso provisional","status":"derivado"},{"label":"Extensión de la malla en Z","value":0.8,"unit":"m","source":"Geometría releída del IFC; datum absoluto de proceso provisional","status":"derivado"},{"label":"Cota inferior de visualización","value":285.5,"unit":"m","source":"Geometría releída del IFC; datum absoluto de proceso provisional","status":"derivado"},{"label":"Cota superior de visualización","value":286.3,"unit":"m","source":"Geometría releída del IFC; datum absoluto de proceso provisional","status":"derivado"}]} | {"documentId":"LHD2609-JG00100-20260904","title":"Cimentaciones de equipos y pedestales del fabricante · revisión recibida 04/09/2026","date":"2026-09-04","sheet":"ZD1 / DZ-1","fileName":"LHD2609-JG00100_20260904.dwg","revisionCaveat":"Fecha de revisión tomada del nombre recibido; cajetines internos mantienen 02/07/2026 y algunos textos de plantilla.","sourceFileSha256":"b42eb027b7bc0b14c38d1d13514f4899b58a732aa8d0ba2ccf10fa2fc3192890"} | provisional | [] | {"Cota inferior relativa (m)":-0.6,"Cota superior relativa (m)":0.2,"Cero absoluto de visualización (m)":286.1,"Estado del cero absoluto":"Provisional","Criterio":"Las cotas relativas proceden del dibujo; la equivalencia absoluta no está confirmada."} | {"boundingBoxM":{"min":[47.977169,78.098115,0.5],"max":[48.484267,78.605213,1.3]},"extentsM":[0.507098,0.507098,0.8],"meshSurfaceM2":1.844999,"meshVolumeM3":0.162,"closedSolid":true,"basis":"Magnitudes de las mallas representadas, no cantidades certificadas de obra, compra o fabricación. Las partes pueden compartir superficies; no se suman como un despiece de materiales."} | {"profileId":"concrete_ha30","name":"Hormigón HA-30","materialName":"Hormigón HA-30","physicalMaterialStatus":"documentado","physicalMaterialSource":"Nota general de pedestales 2CED5","appearanceStatus":"criterio_visual","appearanceBasis":"Interpretación visual del material documental; el acabado, tono y parámetros PBR no son una especificación contractual.","note":"La apariencia gráfica no modifica ni confirma la especificación física del material."} | {"elementId":"found_0904_bd57fef39f7aaf","ifcGuid":"2u8GJAxuTQOvuJvIcJ_nR0","ifcClass":"IfcFooting","buildingId":"process_plant","buildingName":"Zona de separación de aire","sourceDocumentId":"LHD2609-JG00100-20260904","sourceRepresentationKind":"foundation"} | {"layerId":"foundations","layerName":"Cimentaciones","role":"Cimentación industrial","basis":"Clasificación por función del elemento; no modifica las especificaciones documentales."} | {"profileId":"concrete_ha30","name":"Hormigón HA-30","status":"criterio_visual","basis":"Interpretación visual del material documental; el acabado, tono y parámetros PBR no son una especificación contractual.","physicalMaterialUnchanged":true} | 0.162 | Hormigón HA-30 | Hormigón HA-30 | found_0904_bd57fef39f7aaf | Nota general de pedestales 2CED5 | documentado | concrete_ha30 | [0.658824,0.658824,0.623529] | 0.94 | Zona de separación de aire; BIM · Cimentaciones | 0.507098 | 0.507098 | 0.8 | 285.5 | 286.3 | SUP-C02 | [] | ["C02"] | ZD1 / DZ-1 | ["2CC57","2CD32","2CD35","2CD33","2CD30","2CD31","2CD34","2CEA8","2CE83"] | SUP-C02/Cimentación de soporte de tuberías C02 · pedestal de hormigón | foundation | Geometría de fabricante; implantación absoluta provisional |  | Cimentaciones de equipos y pedestales del fabricante · revisión recibida 04/09/2026 | 2CC57, 2CD32, 2CD35, 2CD33, 2CD30, 2CD31, 2CD34, 2CEA8, 2CE83 | -0.6 | 0.2 | 0.2025 | Cotas relativas del dibujo. La equivalencia con un datum absoluto está pendiente. | Z del modelo = cota relativa + 1,10 m. Correspondencia provisional con 286,10 m; no es cota de obra confirmada. | Contornos y sección documentados por el fabricante | 0.45 | 0.45 | Material: Hormigón HA-30
Cimentación de soporte de tuberías C03 · cuerpo de hormigón | Parcela industrial Jinhong | Cimentación industrial | Cimentaciones de equipos y pedestales del fabricante · revisión recibida 04/09/2026 | 1.12689 | 1.12688 | 0.4 | 3.6 | 0.4 | process_plant | Zona de separación de aire | {"name":"Hormigón HA-30","status":"documentado","source":"Nota general de pedestales 2CED5"} | {"documented":[{"label":"Extensión local X","value":1.0,"unit":"m","source":"2CC58, 2CD38, 2CD3B, 2CD39, 2CD36, 2CD37, 2CD3A, 2CEA9, 2CE84","status":"derivada del contorno CAD"},{"label":"Extensión local Y","value":1.0,"unit":"m","source":"2CC58, 2CD38, 2CD3B, 2CD39, 2CD36, 2CD37, 2CD3A, 2CEA9, 2CE84","status":"derivada del contorno CAD"},{"label":"Cota inferior relativa adoptada","value":-1.0,"unit":"m","source":"ZD1 / DZ-1","status":"documentada"},{"label":"Cota superior relativa adoptada","value":-0.6,"unit":"m","source":"ZD1 / DZ-1","status":"documentada / separación por material"}],"geometry":[{"label":"Extensión de la malla en X","value":1.1268850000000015,"unit":"m","source":"Geometría releída del IFC; datum absoluto de proceso provisional","status":"derivado"},{"label":"Extensión de la malla en Y","value":1.126884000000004,"unit":"m","source":"Geometría releída del IFC; datum absoluto de proceso provisional","status":"derivado"},{"label":"Extensión de la malla en Z","value":0.4,"unit":"m","source":"Geometría releída del IFC; datum absoluto de proceso provisional","status":"derivado"},{"label":"Cota inferior de visualización","value":285.1,"unit":"m","source":"Geometría releída del IFC; datum absoluto de proceso provisional","status":"derivado"},{"label":"Cota superior de visualización","value":285.5,"unit":"m","source":"Geometría releída del IFC; datum absoluto de proceso provisional","status":"derivado"}]} | {"documentId":"LHD2609-JG00100-20260904","title":"Cimentaciones de equipos y pedestales del fabricante · revisión recibida 04/09/2026","date":"2026-09-04","sheet":"ZD1 / DZ-1","fileName":"LHD2609-JG00100_20260904.dwg","revisionCaveat":"Fecha de revisión tomada del nombre recibido; cajetines internos mantienen 02/07/2026 y algunos textos de plantilla.","sourceFileSha256":"b42eb027b7bc0b14c38d1d13514f4899b58a732aa8d0ba2ccf10fa2fc3192890"} | provisional | [] | {"Cota inferior relativa (m)":-1.0,"Cota superior relativa (m)":-0.6,"Cero absoluto de visualización (m)":286.1,"Estado del cero absoluto":"Provisional","Criterio":"Las cotas relativas proceden del dibujo; la equivalencia absoluta no está confirmada."} | {"boundingBoxM":{"min":[53.899572,77.966016,0.1],"max":[55.026457,79.0929,0.5]},"extentsM":[1.126885,1.126884,0.4],"meshSurfaceM2":3.599998,"meshVolumeM3":0.4,"closedSolid":true,"basis":"Magnitudes de las mallas representadas, no cantidades certificadas de obra, compra o fabricación. Las partes pueden compartir superficies; no se suman como un despiece de materiales."} | {"profileId":"concrete_ha30","name":"Hormigón HA-30","materialName":"Hormigón HA-30","physicalMaterialStatus":"documentado","physicalMaterialSource":"Nota general de pedestales 2CED5","appearanceStatus":"criterio_visual","appearanceBasis":"Interpretación visual del material documental; el acabado, tono y parámetros PBR no son una especificación contractual.","note":"La apariencia gráfica no modifica ni confirma la especificación física del material."} | {"elementId":"found_0904_12b8880731db4a","ifcGuid":"31a2PBMmXH$hlwCok$7VI2","ifcClass":"IfcFooting","buildingId":"process_plant","buildingName":"Zona de separación de aire","sourceDocumentId":"LHD2609-JG00100-20260904","sourceRepresentationKind":"foundation"} | {"layerId":"foundations","layerName":"Cimentaciones","role":"Cimentación industrial","basis":"Clasificación por función del elemento; no modifica las especificaciones documentales."} | {"profileId":"concrete_ha30","name":"Hormigón HA-30","status":"criterio_visual","basis":"Interpretación visual del material documental; el acabado, tono y parámetros PBR no son una especificación contractual.","physicalMaterialUnchanged":true} | 0.4 | Hormigón HA-30 | Hormigón HA-30 | found_0904_12b8880731db4a | Nota general de pedestales 2CED5 | documentado | concrete_ha30 | [0.658824,0.658824,0.623529] | 0.94 | Zona de separación de aire; BIM · Cimentaciones | 1.12689 | 1.12688 | 0.4 | 285.1 | 285.5 | SUP-C03 | [] | ["C03"] | ZD1 / DZ-1 | ["2CC58","2CD38","2CD3B","2CD39","2CD36","2CD37","2CD3A","2CEA9","2CE84"] | SUP-C03/Cimentación de soporte de tuberías C03 · cuerpo de hormigón | foundation | Geometría de fabricante; implantación absoluta provisional |  | Cimentaciones de equipos y pedestales del fabricante · revisión recibida 04/09/2026 | 2CC58, 2CD38, 2CD3B, 2CD39, 2CD36, 2CD37, 2CD3A, 2CEA9, 2CE84 | -1 | -0.6 | 1 | Cotas relativas del dibujo. La equivalencia con un datum absoluto está pendiente. | Z del modelo = cota relativa + 1,10 m. Correspondencia provisional con 286,10 m; no es cota de obra confirmada. | Contornos y sección documentados por el fabricante | 1 | 1 | Material: Hormigón HA-30
Cimentación de soporte de tuberías C03 · pedestal de hormigón | Parcela industrial Jinhong | Cimentación industrial | Cimentaciones de equipos y pedestales del fabricante · revisión recibida 04/09/2026 | 0.507098 | 0.507098 | 0.8 | 1.845 | 0.162 | process_plant | Zona de separación de aire | {"name":"Hormigón HA-30","status":"documentado","source":"Nota general de pedestales 2CED5"} | {"documented":[{"label":"Extensión local X","value":0.45,"unit":"m","source":"2CC58, 2CD38, 2CD3B, 2CD39, 2CD36, 2CD37, 2CD3A, 2CEA9, 2CE84","status":"derivada del contorno CAD"},{"label":"Extensión local Y","value":0.45,"unit":"m","source":"2CC58, 2CD38, 2CD3B, 2CD39, 2CD36, 2CD37, 2CD3A, 2CEA9, 2CE84","status":"derivada del contorno CAD"},{"label":"Cota inferior relativa adoptada","value":-0.6,"unit":"m","source":"ZD1 / DZ-1","status":"documentada"},{"label":"Cota superior relativa adoptada","value":0.2,"unit":"m","source":"ZD1 / DZ-1","status":"documentada / separación por material"}],"geometry":[{"label":"Extensión de la malla en X","value":0.5070979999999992,"unit":"m","source":"Geometría releída del IFC; datum absoluto de proceso provisional","status":"derivado"},{"label":"Extensión de la malla en Y","value":0.5070979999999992,"unit":"m","source":"Geometría releída del IFC; datum absoluto de proceso provisional","status":"derivado"},{"label":"Extensión de la malla en Z","value":0.8,"unit":"m","source":"Geometría releída del IFC; datum absoluto de proceso provisional","status":"derivado"},{"label":"Cota inferior de visualización","value":285.5,"unit":"m","source":"Geometría releída del IFC; datum absoluto de proceso provisional","status":"derivado"},{"label":"Cota superior de visualización","value":286.3,"unit":"m","source":"Geometría releída del IFC; datum absoluto de proceso provisional","status":"derivado"}]} | {"documentId":"LHD2609-JG00100-20260904","title":"Cimentaciones de equipos y pedestales del fabricante · revisión recibida 04/09/2026","date":"2026-09-04","sheet":"ZD1 / DZ-1","fileName":"LHD2609-JG00100_20260904.dwg","revisionCaveat":"Fecha de revisión tomada del nombre recibido; cajetines internos mantienen 02/07/2026 y algunos textos de plantilla.","sourceFileSha256":"b42eb027b7bc0b14c38d1d13514f4899b58a732aa8d0ba2ccf10fa2fc3192890"} | provisional | [] | {"Cota inferior relativa (m)":-0.6,"Cota superior relativa (m)":0.2,"Cero absoluto de visualización (m)":286.1,"Estado del cero absoluto":"Provisional","Criterio":"Las cotas relativas proceden del dibujo; la equivalencia absoluta no está confirmada."} | {"boundingBoxM":{"min":[54.209465,78.275909,0.5],"max":[54.716563,78.783007,1.3]},"extentsM":[0.507098,0.507098,0.8],"meshSurfaceM2":1.844999,"meshVolumeM3":0.162,"closedSolid":true,"basis":"Magnitudes de las mallas representadas, no cantidades certificadas de obra, compra o fabricación. Las partes pueden compartir superficies; no se suman como un despiece de materiales."} | {"profileId":"concrete_ha30","name":"Hormigón HA-30","materialName":"Hormigón HA-30","physicalMaterialStatus":"documentado","physicalMaterialSource":"Nota general de pedestales 2CED5","appearanceStatus":"criterio_visual","appearanceBasis":"Interpretación visual del material documental; el acabado, tono y parámetros PBR no son una especificación contractual.","note":"La apariencia gráfica no modifica ni confirma la especificación física del material."} | {"elementId":"found_0904_51266d5840ba54","ifcGuid":"3kisbR2urVTxg8sXuWynmL","ifcClass":"IfcFooting","buildingId":"process_plant","buildingName":"Zona de separación de aire","sourceDocumentId":"LHD2609-JG00100-20260904","sourceRepresentationKind":"foundation"} | {"layerId":"foundations","layerName":"Cimentaciones","role":"Cimentación industrial","basis":"Clasificación por función del elemento; no modifica las especificaciones documentales."} | {"profileId":"concrete_ha30","name":"Hormigón HA-30","status":"criterio_visual","basis":"Interpretación visual del material documental; el acabado, tono y parámetros PBR no son una especificación contractual.","physicalMaterialUnchanged":true} | 0.162 | Hormigón HA-30 | Hormigón HA-30 | found_0904_51266d5840ba54 | Nota general de pedestales 2CED5 | documentado | concrete_ha30 | [0.658824,0.658824,0.623529] | 0.94 | Zona de separación de aire; BIM · Cimentaciones | 0.507098 | 0.507098 | 0.8 | 285.5 | 286.3 | SUP-C03 | [] | ["C03"] | ZD1 / DZ-1 | ["2CC58","2CD38","2CD3B","2CD39","2CD36","2CD37","2CD3A","2CEA9","2CE84"] | SUP-C03/Cimentación de soporte de tuberías C03 · pedestal de hormigón | foundation | Geometría de fabricante; implantación absoluta provisional |  | Cimentaciones de equipos y pedestales del fabricante · revisión recibida 04/09/2026 | 2CC58, 2CD38, 2CD3B, 2CD39, 2CD36, 2CD37, 2CD3A, 2CEA9, 2CE84 | -0.6 | 0.2 | 0.2025 | Cotas relativas del dibujo. La equivalencia con un datum absoluto está pendiente. | Z del modelo = cota relativa + 1,10 m. Correspondencia provisional con 286,10 m; no es cota de obra confirmada. | Contornos y sección documentados por el fabricante | 0.45 | 0.45 | Material: Hormigón HA-30
Cimentación de soporte de tuberías C04 · cuerpo de hormigón | Parcela industrial Jinhong | Cimentación industrial | Cimentaciones de equipos y pedestales del fabricante · revisión recibida 04/09/2026 | 1.12689 | 1.12689 | 0.4 | 3.6 | 0.4 | process_plant | Zona de separación de aire | {"name":"Hormigón HA-30","status":"documentado","source":"Nota general de pedestales 2CED5"} | {"documented":[{"label":"Extensión local X","value":1.0,"unit":"m","source":"2CC59, 2CD3E, 2CD41, 2CD3F, 2CD3C, 2CD3D, 2CD40, 2CEAA, 2CE85","status":"derivada del contorno CAD"},{"label":"Extensión local Y","value":1.0,"unit":"m","source":"2CC59, 2CD3E, 2CD41, 2CD3F, 2CD3C, 2CD3D, 2CD40, 2CEAA, 2CE85","status":"derivada del contorno CAD"},{"label":"Cota inferior relativa adoptada","value":-1.0,"unit":"m","source":"ZD1 / DZ-1","status":"documentada"},{"label":"Cota superior relativa adoptada","value":-0.6,"unit":"m","source":"ZD1 / DZ-1","status":"documentada / separación por material"}],"geometry":[{"label":"Extensión de la malla en X","value":1.1268850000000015,"unit":"m","source":"Geometría releída del IFC; datum absoluto de proceso provisional","status":"derivado"},{"label":"Extensión de la malla en Y","value":1.1268850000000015,"unit":"m","source":"Geometría releída del IFC; datum absoluto de proceso provisional","status":"derivado"},{"label":"Extensión de la malla en Z","value":0.4,"unit":"m","source":"Geometría releída del IFC; datum absoluto de proceso provisional","status":"derivado"},{"label":"Cota inferior de visualización","value":285.1,"unit":"m","source":"Geometría releída del IFC; datum absoluto de proceso provisional","status":"derivado"},{"label":"Cota superior de visualización","value":285.5,"unit":"m","source":"Geometría releída del IFC; datum absoluto de proceso provisional","status":"derivado"}]} | {"documentId":"LHD2609-JG00100-20260904","title":"Cimentaciones de equipos y pedestales del fabricante · revisión recibida 04/09/2026","date":"2026-09-04","sheet":"ZD1 / DZ-1","fileName":"LHD2609-JG00100_20260904.dwg","revisionCaveat":"Fecha de revisión tomada del nombre recibido; cajetines internos mantienen 02/07/2026 y algunos textos de plantilla.","sourceFileSha256":"b42eb027b7bc0b14c38d1d13514f4899b58a732aa8d0ba2ccf10fa2fc3192890"} | provisional | [] | {"Cota inferior relativa (m)":-1.0,"Cota superior relativa (m)":-0.6,"Cero absoluto de visualización (m)":286.1,"Estado del cero absoluto":"Provisional","Criterio":"Las cotas relativas proceden del dibujo; la equivalencia absoluta no está confirmada."} | {"boundingBoxM":{"min":[53.759963,76.950568,0.1],"max":[54.886848,78.077453,0.5]},"extentsM":[1.126885,1.126885,0.4],"meshSurfaceM2":3.600001,"meshVolumeM3":0.4,"closedSolid":true,"basis":"Magnitudes de las mallas representadas, no cantidades certificadas de obra, compra o fabricación. Las partes pueden compartir superficies; no se suman como un despiece de materiales."} | {"profileId":"concrete_ha30","name":"Hormigón HA-30","materialName":"Hormigón HA-30","physicalMaterialStatus":"documentado","physicalMaterialSource":"Nota general de pedestales 2CED5","appearanceStatus":"criterio_visual","appearanceBasis":"Interpretación visual del material documental; el acabado, tono y parámetros PBR no son una especificación contractual.","note":"La apariencia gráfica no modifica ni confirma la especificación física del material."} | {"elementId":"found_0904_5bea85d472fdfb","ifcGuid":"29yeLRrqXUW80TD6sROXx2","ifcClass":"IfcFooting","buildingId":"process_plant","buildingName":"Zona de separación de aire","sourceDocumentId":"LHD2609-JG00100-20260904","sourceRepresentationKind":"foundation"} | {"layerId":"foundations","layerName":"Cimentaciones","role":"Cimentación industrial","basis":"Clasificación por función del elemento; no modifica las especificaciones documentales."} | {"profileId":"concrete_ha30","name":"Hormigón HA-30","status":"criterio_visual","basis":"Interpretación visual del material documental; el acabado, tono y parámetros PBR no son una especificación contractual.","physicalMaterialUnchanged":true} | 0.4 | Hormigón HA-30 | Hormigón HA-30 | found_0904_5bea85d472fdfb | Nota general de pedestales 2CED5 | documentado | concrete_ha30 | [0.658824,0.658824,0.623529] | 0.94 | Zona de separación de aire; BIM · Cimentaciones | 1.12689 | 1.12689 | 0.4 | 285.1 | 285.5 | SUP-C04 | [] | ["C04"] | ZD1 / DZ-1 | ["2CC59","2CD3E","2CD41","2CD3F","2CD3C","2CD3D","2CD40","2CEAA","2CE85"] | SUP-C04/Cimentación de soporte de tuberías C04 · cuerpo de hormigón | foundation | Geometría de fabricante; implantación absoluta provisional |  | Cimentaciones de equipos y pedestales del fabricante · revisión recibida 04/09/2026 | 2CC59, 2CD3E, 2CD41, 2CD3F, 2CD3C, 2CD3D, 2CD40, 2CEAA, 2CE85 | -1 | -0.6 | 1 | Cotas relativas del dibujo. La equivalencia con un datum absoluto está pendiente. | Z del modelo = cota relativa + 1,10 m. Correspondencia provisional con 286,10 m; no es cota de obra confirmada. | Contornos y sección documentados por el fabricante | 1 | 1 | Material: Hormigón HA-30
Cimentación de soporte de tuberías C04 · pedestal de hormigón | Parcela industrial Jinhong | Cimentación industrial | Cimentaciones de equipos y pedestales del fabricante · revisión recibida 04/09/2026 | 0.507098 | 0.507098 | 0.8 | 1.845 | 0.162 | process_plant | Zona de separación de aire | {"name":"Hormigón HA-30","status":"documentado","source":"Nota general de pedestales 2CED5"} | {"documented":[{"label":"Extensión local X","value":0.45,"unit":"m","source":"2CC59, 2CD3E, 2CD41, 2CD3F, 2CD3C, 2CD3D, 2CD40, 2CEAA, 2CE85","status":"derivada del contorno CAD"},{"label":"Extensión local Y","value":0.45,"unit":"m","source":"2CC59, 2CD3E, 2CD41, 2CD3F, 2CD3C, 2CD3D, 2CD40, 2CEAA, 2CE85","status":"derivada del contorno CAD"},{"label":"Cota inferior relativa adoptada","value":-0.6,"unit":"m","source":"ZD1 / DZ-1","status":"documentada"},{"label":"Cota superior relativa adoptada","value":0.2,"unit":"m","source":"ZD1 / DZ-1","status":"documentada / separación por material"}],"geometry":[{"label":"Extensión de la malla en X","value":0.5070979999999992,"unit":"m","source":"Geometría releída del IFC; datum absoluto de proceso provisional","status":"derivado"},{"label":"Extensión de la malla en Y","value":0.5070979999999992,"unit":"m","source":"Geometría releída del IFC; datum absoluto de proceso provisional","status":"derivado"},{"label":"Extensión de la malla en Z","value":0.8,"unit":"m","source":"Geometría releída del IFC; datum absoluto de proceso provisional","status":"derivado"},{"label":"Cota inferior de visualización","value":285.5,"unit":"m","source":"Geometría releída del IFC; datum absoluto de proceso provisional","status":"derivado"},{"label":"Cota superior de visualización","value":286.3,"unit":"m","source":"Geometría releída del IFC; datum absoluto de proceso provisional","status":"derivado"}]} | {"documentId":"LHD2609-JG00100-20260904","title":"Cimentaciones de equipos y pedestales del fabricante · revisión recibida 04/09/2026","date":"2026-09-04","sheet":"ZD1 / DZ-1","fileName":"LHD2609-JG00100_20260904.dwg","revisionCaveat":"Fecha de revisión tomada del nombre recibido; cajetines internos mantienen 02/07/2026 y algunos textos de plantilla.","sourceFileSha256":"b42eb027b7bc0b14c38d1d13514f4899b58a732aa8d0ba2ccf10fa2fc3192890"} | provisional | [] | {"Cota inferior relativa (m)":-0.6,"Cota superior relativa (m)":0.2,"Cero absoluto de visualización (m)":286.1,"Estado del cero absoluto":"Provisional","Criterio":"Las cotas relativas proceden del dibujo; la equivalencia absoluta no está confirmada."} | {"boundingBoxM":{"min":[54.069856,77.260461,0.5],"max":[54.576954,77.767559,1.3]},"extentsM":[0.507098,0.507098,0.8],"meshSurfaceM2":1.844998,"meshVolumeM3":0.162,"closedSolid":true,"basis":"Magnitudes de las mallas representadas, no cantidades certificadas de obra, compra o fabricación. Las partes pueden compartir superficies; no se suman como un despiece de materiales."} | {"profileId":"concrete_ha30","name":"Hormigón HA-30","materialName":"Hormigón HA-30","physicalMaterialStatus":"documentado","physicalMaterialSource":"Nota general de pedestales 2CED5","appearanceStatus":"criterio_visual","appearanceBasis":"Interpretación visual del material documental; el acabado, tono y parámetros PBR no son una especificación contractual.","note":"La apariencia gráfica no modifica ni confirma la especificación física del material."} | {"elementId":"found_0904_db397e96141385","ifcGuid":"0E7celO$nHHwnIBmL_PzdK","ifcClass":"IfcFooting","buildingId":"process_plant","buildingName":"Zona de separación de aire","sourceDocumentId":"LHD2609-JG00100-20260904","sourceRepresentationKind":"foundation"} | {"layerId":"foundations","layerName":"Cimentaciones","role":"Cimentación industrial","basis":"Clasificación por función del elemento; no modifica las especificaciones documentales."} | {"profileId":"concrete_ha30","name":"Hormigón HA-30","status":"criterio_visual","basis":"Interpretación visual del material documental; el acabado, tono y parámetros PBR no son una especificación contractual.","physicalMaterialUnchanged":true} | 0.162 | Hormigón HA-30 | Hormigón HA-30 | found_0904_db397e96141385 | Nota general de pedestales 2CED5 | documentado | concrete_ha30 | [0.658824,0.658824,0.623529] | 0.94 | Zona de separación de aire; BIM · Cimentaciones | 0.507098 | 0.507098 | 0.8 | 285.5 | 286.3 | SUP-C04 | [] | ["C04"] | ZD1 / DZ-1 | ["2CC59","2CD3E","2CD41","2CD3F","2CD3C","2CD3D","2CD40","2CEAA","2CE85"] | SUP-C04/Cimentación de soporte de tuberías C04 · pedestal de hormigón | foundation | Geometría de fabricante; implantación absoluta provisional |  | Cimentaciones de equipos y pedestales del fabricante · revisión recibida 04/09/2026 | 2CC59, 2CD3E, 2CD41, 2CD3F, 2CD3C, 2CD3D, 2CD40, 2CEAA, 2CE85 | -0.6 | 0.2 | 0.2025 | Cotas relativas del dibujo. La equivalencia con un datum absoluto está pendiente. | Z del modelo = cota relativa + 1,10 m. Correspondencia provisional con 286,10 m; no es cota de obra confirmada. | Contornos y sección documentados por el fabricante | 0.45 | 0.45 | Material: Hormigón HA-30
Cimentación de soporte de tuberías C05 · cuerpo de hormigón | Parcela industrial Jinhong | Cimentación industrial | Cimentaciones de equipos y pedestales del fabricante · revisión recibida 04/09/2026 | 1.12689 | 1.12689 | 0.4 | 3.6 | 0.4 | process_plant | Zona de separación de aire | {"name":"Hormigón HA-30","status":"documentado","source":"Nota general de pedestales 2CED5"} | {"documented":[{"label":"Extensión local X","value":1.0,"unit":"m","source":"2CC5A, 2CD42, 2CC62, 2CC66, 2CC22, 2CC29, 2CD67, 2CEAB, 2CE86","status":"derivada del contorno CAD"},{"label":"Extensión local Y","value":1.0,"unit":"m","source":"2CC5A, 2CD42, 2CC62, 2CC66, 2CC22, 2CC29, 2CD67, 2CEAB, 2CE86","status":"derivada del contorno CAD"},{"label":"Cota inferior relativa adoptada","value":-1.0,"unit":"m","source":"ZD1 / DZ-1","status":"documentada"},{"label":"Cota superior relativa adoptada","value":-0.6,"unit":"m","source":"ZD1 / DZ-1","status":"documentada / separación por material"}],"geometry":[{"label":"Extensión de la malla en X","value":1.1268850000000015,"unit":"m","source":"Geometría releída del IFC; datum absoluto de proceso provisional","status":"derivado"},{"label":"Extensión de la malla en Y","value":1.1268850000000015,"unit":"m","source":"Geometría releída del IFC; datum absoluto de proceso provisional","status":"derivado"},{"label":"Extensión de la malla en Z","value":0.4,"unit":"m","source":"Geometría releída del IFC; datum absoluto de proceso provisional","status":"derivado"},{"label":"Cota inferior de visualización","value":285.1,"unit":"m","source":"Geometría releída del IFC; datum absoluto de proceso provisional","status":"derivado"},{"label":"Cota superior de visualización","value":285.5,"unit":"m","source":"Geometría releída del IFC; datum absoluto de proceso provisional","status":"derivado"}]} | {"documentId":"LHD2609-JG00100-20260904","title":"Cimentaciones de equipos y pedestales del fabricante · revisión recibida 04/09/2026","date":"2026-09-04","sheet":"ZD1 / DZ-1","fileName":"LHD2609-JG00100_20260904.dwg","revisionCaveat":"Fecha de revisión tomada del nombre recibido; cajetines internos mantienen 02/07/2026 y algunos textos de plantilla.","sourceFileSha256":"b42eb027b7bc0b14c38d1d13514f4899b58a732aa8d0ba2ccf10fa2fc3192890"} | provisional | [] | {"Cota inferior relativa (m)":-1.0,"Cota superior relativa (m)":-0.6,"Cero absoluto de visualización (m)":286.1,"Estado del cero absoluto":"Provisional","Criterio":"Las cotas relativas proceden del dibujo; la equivalencia absoluta no está confirmada."} | {"boundingBoxM":{"min":[60.091327,77.114741,0.1],"max":[61.218212,78.241626,0.5]},"extentsM":[1.126885,1.126885,0.4],"meshSurfaceM2":3.600001,"meshVolumeM3":0.4,"closedSolid":true,"basis":"Magnitudes de las mallas representadas, no cantidades certificadas de obra, compra o fabricación. Las partes pueden compartir superficies; no se suman como un despiece de materiales."} | {"profileId":"concrete_ha30","name":"Hormigón HA-30","materialName":"Hormigón HA-30","physicalMaterialStatus":"documentado","physicalMaterialSource":"Nota general de pedestales 2CED5","appearanceStatus":"criterio_visual","appearanceBasis":"Interpretación visual del material documental; el acabado, tono y parámetros PBR no son una especificación contractual.","note":"La apariencia gráfica no modifica ni confirma la especificación física del material."} | {"elementId":"found_0904_787ac93d9d5543","ifcGuid":"2NjgcIvADU_RT9rTv491$M","ifcClass":"IfcFooting","buildingId":"process_plant","buildingName":"Zona de separación de aire","sourceDocumentId":"LHD2609-JG00100-20260904","sourceRepresentationKind":"foundation"} | {"layerId":"foundations","layerName":"Cimentaciones","role":"Cimentación industrial","basis":"Clasificación por función del elemento; no modifica las especificaciones documentales."} | {"profileId":"concrete_ha30","name":"Hormigón HA-30","status":"criterio_visual","basis":"Interpretación visual del material documental; el acabado, tono y parámetros PBR no son una especificación contractual.","physicalMaterialUnchanged":true} | 0.4 | Hormigón HA-30 | Hormigón HA-30 | found_0904_787ac93d9d5543 | Nota general de pedestales 2CED5 | documentado | concrete_ha30 | [0.658824,0.658824,0.623529] | 0.94 | Zona de separación de aire; BIM · Cimentaciones | 1.12689 | 1.12689 | 0.4 | 285.1 | 285.5 | SUP-C05 | [] | ["C05"] | ZD1 / DZ-1 | ["2CC5A","2CD42","2CC62","2CC66","2CC22","2CC29","2CD67","2CEAB","2CE86"] | SUP-C05/Cimentación de soporte de tuberías C05 · cuerpo de hormigón | foundation | Geometría de fabricante; implantación absoluta provisional |  | Cimentaciones de equipos y pedestales del fabricante · revisión recibida 04/09/2026 | 2CC5A, 2CD42, 2CC62, 2CC66, 2CC22, 2CC29, 2CD67, 2CEAB, 2CE86 | -1 | -0.6 | 1 | Cotas relativas del dibujo. La equivalencia con un datum absoluto está pendiente. | Z del modelo = cota relativa + 1,10 m. Correspondencia provisional con 286,10 m; no es cota de obra confirmada. | Contornos y sección documentados por el fabricante | 1 | 1 | Material: Hormigón HA-30
Cimentación de soporte de tuberías C05 · pedestal de hormigón | Parcela industrial Jinhong | Cimentación industrial | Cimentaciones de equipos y pedestales del fabricante · revisión recibida 04/09/2026 | 0.507098 | 0.507099 | 0.8 | 1.845 | 0.162 | process_plant | Zona de separación de aire | {"name":"Hormigón HA-30","status":"documentado","source":"Nota general de pedestales 2CED5"} | {"documented":[{"label":"Extensión local X","value":0.45,"unit":"m","source":"2CC5A, 2CD42, 2CC62, 2CC66, 2CC22, 2CC29, 2CD67, 2CEAB, 2CE86","status":"derivada del contorno CAD"},{"label":"Extensión local Y","value":0.45,"unit":"m","source":"2CC5A, 2CD42, 2CC62, 2CC66, 2CC22, 2CC29, 2CD67, 2CEAB, 2CE86","status":"derivada del contorno CAD"},{"label":"Cota inferior relativa adoptada","value":-0.6,"unit":"m","source":"ZD1 / DZ-1","status":"documentada"},{"label":"Cota superior relativa adoptada","value":0.2,"unit":"m","source":"ZD1 / DZ-1","status":"documentada / separación por material"}],"geometry":[{"label":"Extensión de la malla en X","value":0.5070979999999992,"unit":"m","source":"Geometría releída del IFC; datum absoluto de proceso provisional","status":"derivado"},{"label":"Extensión de la malla en Y","value":0.5070989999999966,"unit":"m","source":"Geometría releída del IFC; datum absoluto de proceso provisional","status":"derivado"},{"label":"Extensión de la malla en Z","value":0.8,"unit":"m","source":"Geometría releída del IFC; datum absoluto de proceso provisional","status":"derivado"},{"label":"Cota inferior de visualización","value":285.5,"unit":"m","source":"Geometría releída del IFC; datum absoluto de proceso provisional","status":"derivado"},{"label":"Cota superior de visualización","value":286.3,"unit":"m","source":"Geometría releída del IFC; datum absoluto de proceso provisional","status":"derivado"}]} | {"documentId":"LHD2609-JG00100-20260904","title":"Cimentaciones de equipos y pedestales del fabricante · revisión recibida 04/09/2026","date":"2026-09-04","sheet":"ZD1 / DZ-1","fileName":"LHD2609-JG00100_20260904.dwg","revisionCaveat":"Fecha de revisión tomada del nombre recibido; cajetines internos mantienen 02/07/2026 y algunos textos de plantilla.","sourceFileSha256":"b42eb027b7bc0b14c38d1d13514f4899b58a732aa8d0ba2ccf10fa2fc3192890"} | provisional | [] | {"Cota inferior relativa (m)":-0.6,"Cota superior relativa (m)":0.2,"Cero absoluto de visualización (m)":286.1,"Estado del cero absoluto":"Provisional","Criterio":"Las cotas relativas proceden del dibujo; la equivalencia absoluta no está confirmada."} | {"boundingBoxM":{"min":[60.40122,77.424634,0.5],"max":[60.908318,77.931733,1.3]},"extentsM":[0.507098,0.507099,0.8],"meshSurfaceM2":1.845002,"meshVolumeM3":0.162,"closedSolid":true,"basis":"Magnitudes de las mallas representadas, no cantidades certificadas de obra, compra o fabricación. Las partes pueden compartir superficies; no se suman como un despiece de materiales."} | {"profileId":"concrete_ha30","name":"Hormigón HA-30","materialName":"Hormigón HA-30","physicalMaterialStatus":"documentado","physicalMaterialSource":"Nota general de pedestales 2CED5","appearanceStatus":"criterio_visual","appearanceBasis":"Interpretación visual del material documental; el acabado, tono y parámetros PBR no son una especificación contractual.","note":"La apariencia gráfica no modifica ni confirma la especificación física del material."} | {"elementId":"found_0904_67ad3743b6605e","ifcGuid":"0t2FmvegLRxwKdQT67i9yB","ifcClass":"IfcFooting","buildingId":"process_plant","buildingName":"Zona de separación de aire","sourceDocumentId":"LHD2609-JG00100-20260904","sourceRepresentationKind":"foundation"} | {"layerId":"foundations","layerName":"Cimentaciones","role":"Cimentación industrial","basis":"Clasificación por función del elemento; no modifica las especificaciones documentales."} | {"profileId":"concrete_ha30","name":"Hormigón HA-30","status":"criterio_visual","basis":"Interpretación visual del material documental; el acabado, tono y parámetros PBR no son una especificación contractual.","physicalMaterialUnchanged":true} | 0.162 | Hormigón HA-30 | Hormigón HA-30 | found_0904_67ad3743b6605e | Nota general de pedestales 2CED5 | documentado | concrete_ha30 | [0.658824,0.658824,0.623529] | 0.94 | Zona de separación de aire; BIM · Cimentaciones | 0.507098 | 0.507099 | 0.8 | 285.5 | 286.3 | SUP-C05 | [] | ["C05"] | ZD1 / DZ-1 | ["2CC5A","2CD42","2CC62","2CC66","2CC22","2CC29","2CD67","2CEAB","2CE86"] | SUP-C05/Cimentación de soporte de tuberías C05 · pedestal de hormigón | foundation | Geometría de fabricante; implantación absoluta provisional |  | Cimentaciones de equipos y pedestales del fabricante · revisión recibida 04/09/2026 | 2CC5A, 2CD42, 2CC62, 2CC66, 2CC22, 2CC29, 2CD67, 2CEAB, 2CE86 | -0.6 | 0.2 | 0.2025 | Cotas relativas del dibujo. La equivalencia con un datum absoluto está pendiente. | Z del modelo = cota relativa + 1,10 m. Correspondencia provisional con 286,10 m; no es cota de obra confirmada. | Contornos y sección documentados por el fabricante | 0.45 | 0.45 | Material: Hormigón HA-30
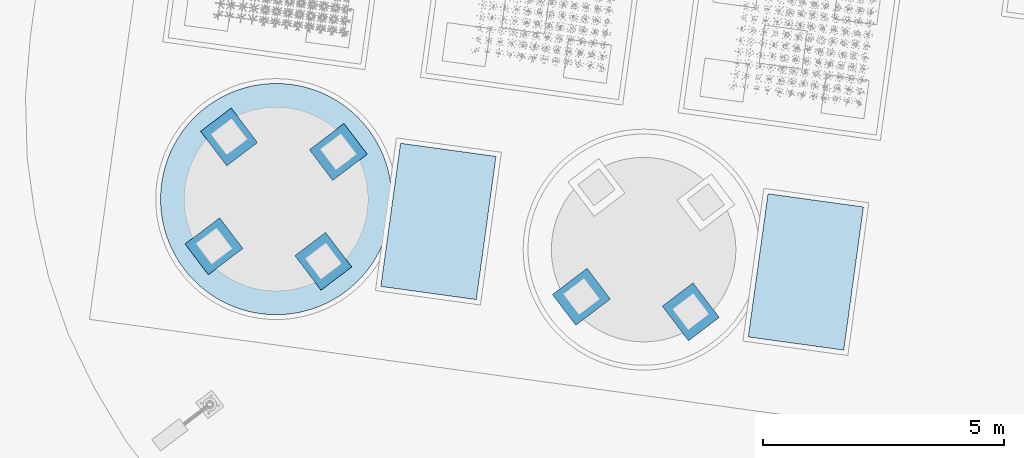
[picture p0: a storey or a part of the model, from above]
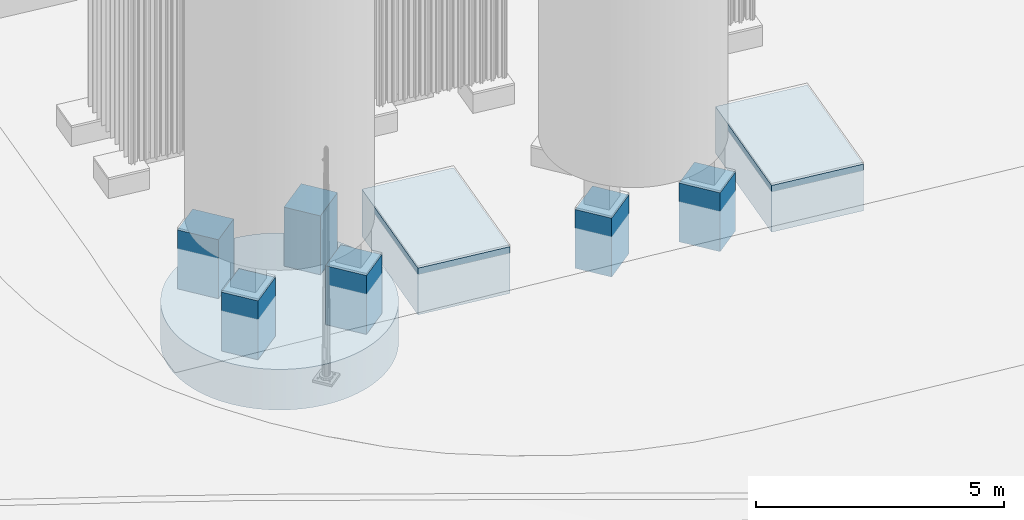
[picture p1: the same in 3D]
Properties of the parts of a building model (IFC4), part 79 of 134

# IfcFooting (214)
Name | In | Description = category = Categoria = Funcion | Document | ExtensionX (m) | ExtensionY (m) | ExtensionZ (m) | SuperficieDeLaMalla (m2) | VolumenGeometrico (m3) | buildingId | buildingName | material | dimensions | JH_InformacionBIM, source = DocumentoFuente | JH_InformacionBIM, status = EstadoDeInformacion | issues = IncidenciasPendientes | positioning = PosicionYEstado | geometryMetrics | materialAppearance | visualizationIdentity | classification | appearance | Volumen geométrico (m³) | JH_Trazabilidad, Material = name | Acabado de visualización = Acabado | Identificador | JH_EvidenciaDeMaterial, source | JH_EvidenciaDeMaterial, status | Perfil | ColorRGB | Rugosidad | Group | Extensión de la malla en X (m) | Extensión de la malla en Y (m) | Extensión de la malla en Z (m) = Espesor o altura real de sección (m) | Cota inferior de visualización (m) | Cota superior de visualización (m) | assemblyId = Conjunto de cimentación | equipmentIds | supportPositionIds | sectionRef = Sección de referencia | sourceCadHandles | stableElementKey | representationKind | geometryStatus | Equipos asociados | Documento de origen | Identificadores CAD de referencia | Cota inferior relativa (m) = Cota inferior relativa adoptada (m) | Cota superior relativa (m) = Cota superior relativa adoptada (m) | Área de planta (m²) | Referencia vertical | Implantación para visualización | Estado de la geometría | Extensión local X (m) | Extensión local Y (m) | Incidencias de origen
Cimentación de soporte de tuberías C06 · cuerpo de hormigón | Parcela industrial Jinhong | Cimentación industrial | Cimentaciones de equipos y pedestales del fabricante · revisión recibida 04/09/2026 | 1.12689 | 1.12689 | 0.4 | 3.6 | 0.4 | process_plant | Zona de separación de aire | {"name":"Hormigón HA-30","status":"documentado","source":"Nota general de pedestales 2CED5"} | {"documented":[{"label":"Extensión local X","value":1.0,"unit":"m","source":"2CC5B, 2CD43, 2CC63, 2CC67, 2CC23, 2CC2A, 2CD68, 2CEAC, 2CE87","status":"derivada del contorno CAD"},{"label":"Extensión local Y","value":1.0,"unit":"m","source":"2CC5B, 2CD43, 2CC63, 2CC67, 2CC23, 2CC2A, 2CD68, 2CEAC, 2CE87","status":"derivada del contorno CAD"},{"label":"Cota inferior relativa adoptada","value":-1.0,"unit":"m","source":"ZD1 / DZ-1","status":"documentada"},{"label":"Cota superior relativa adoptada","value":-0.6,"unit":"m","source":"ZD1 / DZ-1","status":"documentada / separación por material"}],"geometry":[{"label":"Extensión de la malla en X","value":1.1268850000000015,"unit":"m","source":"Geometría releída del IFC; datum absoluto de proceso provisional","status":"derivado"},{"label":"Extensión de la malla en Y","value":1.1268850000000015,"unit":"m","source":"Geometría releída del IFC; datum absoluto de proceso provisional","status":"derivado"},{"label":"Extensión de la malla en Z","value":0.4,"unit":"m","source":"Geometría releída del IFC; datum absoluto de proceso provisional","status":"derivado"},{"label":"Cota inferior de visualización","value":285.1,"unit":"m","source":"Geometría releída del IFC; datum absoluto de proceso provisional","status":"derivado"},{"label":"Cota superior de visualización","value":285.5,"unit":"m","source":"Geometría releída del IFC; datum absoluto de proceso provisional","status":"derivado"}]} | {"documentId":"LHD2609-JG00100-20260904","title":"Cimentaciones de equipos y pedestales del fabricante · revisión recibida 04/09/2026","date":"2026-09-04","sheet":"ZD1 / DZ-1","fileName":"LHD2609-JG00100_20260904.dwg","revisionCaveat":"Fecha de revisión tomada del nombre recibido; cajetines internos mantienen 02/07/2026 y algunos textos de plantilla.","sourceFileSha256":"b42eb027b7bc0b14c38d1d13514f4899b58a732aa8d0ba2ccf10fa2fc3192890"} | provisional | [] | {"Cota inferior relativa (m)":-1.0,"Cota superior relativa (m)":-0.6,"Cero absoluto de visualización (m)":286.1,"Estado del cero absoluto":"Provisional","Criterio":"Las cotas relativas proceden del dibujo; la equivalencia absoluta no está confirmada."} | {"boundingBoxM":{"min":[59.951718,76.099293,0.1],"max":[61.078603,77.226178,0.5]},"extentsM":[1.126885,1.126885,0.4],"meshSurfaceM2":3.600001,"meshVolumeM3":0.4,"closedSolid":true,"basis":"Magnitudes de las mallas representadas, no cantidades certificadas de obra, compra o fabricación. Las partes pueden compartir superficies; no se suman como un despiece de materiales."} | {"profileId":"concrete_ha30","name":"Hormigón HA-30","materialName":"Hormigón HA-30","physicalMaterialStatus":"documentado","physicalMaterialSource":"Nota general de pedestales 2CED5","appearanceStatus":"criterio_visual","appearanceBasis":"Interpretación visual del material documental; el acabado, tono y parámetros PBR no son una especificación contractual.","note":"La apariencia gráfica no modifica ni confirma la especificación física del material."} | {"elementId":"found_0904_9b610ed52ad90e","ifcGuid":"2lw$nYmEjKavC1Xmg7oJS4","ifcClass":"IfcFooting","buildingId":"process_plant","buildingName":"Zona de separación de aire","sourceDocumentId":"LHD2609-JG00100-20260904","sourceRepresentationKind":"foundation"} | {"layerId":"foundations","layerName":"Cimentaciones","role":"Cimentación industrial","basis":"Clasificación por función del elemento; no modifica las especificaciones documentales."} | {"profileId":"concrete_ha30","name":"Hormigón HA-30","status":"criterio_visual","basis":"Interpretación visual del material documental; el acabado, tono y parámetros PBR no son una especificación contractual.","physicalMaterialUnchanged":true} | 0.4 | Hormigón HA-30 | Hormigón HA-30 | found_0904_9b610ed52ad90e | Nota general de pedestales 2CED5 | documentado | concrete_ha30 | [0.658824,0.658824,0.623529] | 0.94 | Zona de separación de aire; BIM · Cimentaciones | 1.12689 | 1.12689 | 0.4 | 285.1 | 285.5 | SUP-C06 | [] | ["C06"] | ZD1 / DZ-1 | ["2CC5B","2CD43","2CC63","2CC67","2CC23","2CC2A","2CD68","2CEAC","2CE87"] | SUP-C06/Cimentación de soporte de tuberías C06 · cuerpo de hormigón | foundation | Geometría de fabricante; implantación absoluta provisional |  | Cimentaciones de equipos y pedestales del fabricante · revisión recibida 04/09/2026 | 2CC5B, 2CD43, 2CC63, 2CC67, 2CC23, 2CC2A, 2CD68, 2CEAC, 2CE87 | -1 | -0.6 | 1 | Cotas relativas del dibujo. La equivalencia con un datum absoluto está pendiente. | Z del modelo = cota relativa + 1,10 m. Correspondencia provisional con 286,10 m; no es cota de obra confirmada. | Contornos y sección documentados por el fabricante | 1 | 1 | Material: Hormigón HA-30
Cimentación de soporte de tuberías C06 · pedestal de hormigón | Parcela industrial Jinhong | Cimentación industrial | Cimentaciones de equipos y pedestales del fabricante · revisión recibida 04/09/2026 | 0.507098 | 0.507098 | 0.8 | 1.845 | 0.162 | process_plant | Zona de separación de aire | {"name":"Hormigón HA-30","status":"documentado","source":"Nota general de pedestales 2CED5"} | {"documented":[{"label":"Extensión local X","value":0.45,"unit":"m","source":"2CC5B, 2CD43, 2CC63, 2CC67, 2CC23, 2CC2A, 2CD68, 2CEAC, 2CE87","status":"derivada del contorno CAD"},{"label":"Extensión local Y","value":0.45,"unit":"m","source":"2CC5B, 2CD43, 2CC63, 2CC67, 2CC23, 2CC2A, 2CD68, 2CEAC, 2CE87","status":"derivada del contorno CAD"},{"label":"Cota inferior relativa adoptada","value":-0.6,"unit":"m","source":"ZD1 / DZ-1","status":"documentada"},{"label":"Cota superior relativa adoptada","value":0.2,"unit":"m","source":"ZD1 / DZ-1","status":"documentada / separación por material"}],"geometry":[{"label":"Extensión de la malla en X","value":0.5070979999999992,"unit":"m","source":"Geometría releída del IFC; datum absoluto de proceso provisional","status":"derivado"},{"label":"Extensión de la malla en Y","value":0.5070979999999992,"unit":"m","source":"Geometría releída del IFC; datum absoluto de proceso provisional","status":"derivado"},{"label":"Extensión de la malla en Z","value":0.8,"unit":"m","source":"Geometría releída del IFC; datum absoluto de proceso provisional","status":"derivado"},{"label":"Cota inferior de visualización","value":285.5,"unit":"m","source":"Geometría releída del IFC; datum absoluto de proceso provisional","status":"derivado"},{"label":"Cota superior de visualización","value":286.3,"unit":"m","source":"Geometría releída del IFC; datum absoluto de proceso provisional","status":"derivado"}]} | {"documentId":"LHD2609-JG00100-20260904","title":"Cimentaciones de equipos y pedestales del fabricante · revisión recibida 04/09/2026","date":"2026-09-04","sheet":"ZD1 / DZ-1","fileName":"LHD2609-JG00100_20260904.dwg","revisionCaveat":"Fecha de revisión tomada del nombre recibido; cajetines internos mantienen 02/07/2026 y algunos textos de plantilla.","sourceFileSha256":"b42eb027b7bc0b14c38d1d13514f4899b58a732aa8d0ba2ccf10fa2fc3192890"} | provisional | [] | {"Cota inferior relativa (m)":-0.6,"Cota superior relativa (m)":0.2,"Cero absoluto de visualización (m)":286.1,"Estado del cero absoluto":"Provisional","Criterio":"Las cotas relativas proceden del dibujo; la equivalencia absoluta no está confirmada."} | {"boundingBoxM":{"min":[60.261611,76.409187,0.5],"max":[60.768709,76.916285,1.3]},"extentsM":[0.507098,0.507098,0.8],"meshSurfaceM2":1.845,"meshVolumeM3":0.162,"closedSolid":true,"basis":"Magnitudes de las mallas representadas, no cantidades certificadas de obra, compra o fabricación. Las partes pueden compartir superficies; no se suman como un despiece de materiales."} | {"profileId":"concrete_ha30","name":"Hormigón HA-30","materialName":"Hormigón HA-30","physicalMaterialStatus":"documentado","physicalMaterialSource":"Nota general de pedestales 2CED5","appearanceStatus":"criterio_visual","appearanceBasis":"Interpretación visual del material documental; el acabado, tono y parámetros PBR no son una especificación contractual.","note":"La apariencia gráfica no modifica ni confirma la especificación física del material."} | {"elementId":"found_0904_dbd98abf123ce2","ifcGuid":"0Pszv$GwPS$BzC9v8p9lZo","ifcClass":"IfcFooting","buildingId":"process_plant","buildingName":"Zona de separación de aire","sourceDocumentId":"LHD2609-JG00100-20260904","sourceRepresentationKind":"foundation"} | {"layerId":"foundations","layerName":"Cimentaciones","role":"Cimentación industrial","basis":"Clasificación por función del elemento; no modifica las especificaciones documentales."} | {"profileId":"concrete_ha30","name":"Hormigón HA-30","status":"criterio_visual","basis":"Interpretación visual del material documental; el acabado, tono y parámetros PBR no son una especificación contractual.","physicalMaterialUnchanged":true} | 0.162 | Hormigón HA-30 | Hormigón HA-30 | found_0904_dbd98abf123ce2 | Nota general de pedestales 2CED5 | documentado | concrete_ha30 | [0.658824,0.658824,0.623529] | 0.94 | Zona de separación de aire; BIM · Cimentaciones | 0.507098 | 0.507098 | 0.8 | 285.5 | 286.3 | SUP-C06 | [] | ["C06"] | ZD1 / DZ-1 | ["2CC5B","2CD43","2CC63","2CC67","2CC23","2CC2A","2CD68","2CEAC","2CE87"] | SUP-C06/Cimentación de soporte de tuberías C06 · pedestal de hormigón | foundation | Geometría de fabricante; implantación absoluta provisional |  | Cimentaciones de equipos y pedestales del fabricante · revisión recibida 04/09/2026 | 2CC5B, 2CD43, 2CC63, 2CC67, 2CC23, 2CC2A, 2CD68, 2CEAC, 2CE87 | -0.6 | 0.2 | 0.2025 | Cotas relativas del dibujo. La equivalencia con un datum absoluto está pendiente. | Z del modelo = cota relativa + 1,10 m. Correspondencia provisional con 286,10 m; no es cota de obra confirmada. | Contornos y sección documentados por el fabricante | 0.45 | 0.45 | Material: Hormigón HA-30
Cimentación de soporte de tuberías C07 · cuerpo de hormigón | Parcela industrial Jinhong | Cimentación industrial | Cimentaciones de equipos y pedestales del fabricante · revisión recibida 04/09/2026 | 1.12689 | 1.12689 | 0.4 | 3.6 | 0.4 | process_plant | Zona de separación de aire | {"name":"Hormigón HA-30","status":"documentado","source":"Nota general de pedestales 2CED5"} | {"documented":[{"label":"Extensión local X","value":1.0,"unit":"m","source":"2CC5C, 2CD44, 2CC60, 2CC68, 2CC24, 2CC2B, 2CD69, 2CEAD, 2CE88","status":"derivada del contorno CAD"},{"label":"Extensión local Y","value":1.0,"unit":"m","source":"2CC5C, 2CD44, 2CC60, 2CC68, 2CC24, 2CC2B, 2CD69, 2CEAD, 2CE88","status":"derivada del contorno CAD"},{"label":"Cota inferior relativa adoptada","value":-1.0,"unit":"m","source":"ZD1 / DZ-1","status":"documentada"},{"label":"Cota superior relativa adoptada","value":-0.6,"unit":"m","source":"ZD1 / DZ-1","status":"documentada / separación por material"}],"geometry":[{"label":"Extensión de la malla en X","value":1.1268850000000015,"unit":"m","source":"Geometría releída del IFC; datum absoluto de proceso provisional","status":"derivado"},{"label":"Extensión de la malla en Y","value":1.1268850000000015,"unit":"m","source":"Geometría releída del IFC; datum absoluto de proceso provisional","status":"derivado"},{"label":"Extensión de la malla en Z","value":0.4,"unit":"m","source":"Geometría releída del IFC; datum absoluto de proceso provisional","status":"derivado"},{"label":"Cota inferior de visualización","value":285.1,"unit":"m","source":"Geometría releída del IFC; datum absoluto de proceso provisional","status":"derivado"},{"label":"Cota superior de visualización","value":285.5,"unit":"m","source":"Geometría releída del IFC; datum absoluto de proceso provisional","status":"derivado"}]} | {"documentId":"LHD2609-JG00100-20260904","title":"Cimentaciones de equipos y pedestales del fabricante · revisión recibida 04/09/2026","date":"2026-09-04","sheet":"ZD1 / DZ-1","fileName":"LHD2609-JG00100_20260904.dwg","revisionCaveat":"Fecha de revisión tomada del nombre recibido; cajetines internos mantienen 02/07/2026 y algunos textos de plantilla.","sourceFileSha256":"b42eb027b7bc0b14c38d1d13514f4899b58a732aa8d0ba2ccf10fa2fc3192890"} | provisional | [] | {"Cota inferior relativa (m)":-1.0,"Cota superior relativa (m)":-0.6,"Cero absoluto de visualización (m)":286.1,"Estado del cero absoluto":"Provisional","Criterio":"Las cotas relativas proceden del dibujo; la equivalencia absoluta no está confirmada."} | {"boundingBoxM":{"min":[45.387837,74.24063,0.1],"max":[46.514722,75.367515,0.5]},"extentsM":[1.126885,1.126885,0.4],"meshSurfaceM2":3.600001,"meshVolumeM3":0.4,"closedSolid":true,"basis":"Magnitudes de las mallas representadas, no cantidades certificadas de obra, compra o fabricación. Las partes pueden compartir superficies; no se suman como un despiece de materiales."} | {"profileId":"concrete_ha30","name":"Hormigón HA-30","materialName":"Hormigón HA-30","physicalMaterialStatus":"documentado","physicalMaterialSource":"Nota general de pedestales 2CED5","appearanceStatus":"criterio_visual","appearanceBasis":"Interpretación visual del material documental; el acabado, tono y parámetros PBR no son una especificación contractual.","note":"La apariencia gráfica no modifica ni confirma la especificación física del material."} | {"elementId":"found_0904_ccba88376aa97d","ifcGuid":"3Ypy$hP69GvwVA6lHGKzSl","ifcClass":"IfcFooting","buildingId":"process_plant","buildingName":"Zona de separación de aire","sourceDocumentId":"LHD2609-JG00100-20260904","sourceRepresentationKind":"foundation"} | {"layerId":"foundations","layerName":"Cimentaciones","role":"Cimentación industrial","basis":"Clasificación por función del elemento; no modifica las especificaciones documentales."} | {"profileId":"concrete_ha30","name":"Hormigón HA-30","status":"criterio_visual","basis":"Interpretación visual del material documental; el acabado, tono y parámetros PBR no son una especificación contractual.","physicalMaterialUnchanged":true} | 0.4 | Hormigón HA-30 | Hormigón HA-30 | found_0904_ccba88376aa97d | Nota general de pedestales 2CED5 | documentado | concrete_ha30 | [0.658824,0.658824,0.623529] | 0.94 | Zona de separación de aire; BIM · Cimentaciones | 1.12689 | 1.12689 | 0.4 | 285.1 | 285.5 | SUP-C07 | [] | ["C07"] | ZD1 / DZ-1 | ["2CC5C","2CD44","2CC60","2CC68","2CC24","2CC2B","2CD69","2CEAD","2CE88"] | SUP-C07/Cimentación de soporte de tuberías C07 · cuerpo de hormigón | foundation | Geometría de fabricante; implantación absoluta provisional |  | Cimentaciones de equipos y pedestales del fabricante · revisión recibida 04/09/2026 | 2CC5C, 2CD44, 2CC60, 2CC68, 2CC24, 2CC2B, 2CD69, 2CEAD, 2CE88 | -1 | -0.6 | 1 | Cotas relativas del dibujo. La equivalencia con un datum absoluto está pendiente. | Z del modelo = cota relativa + 1,10 m. Correspondencia provisional con 286,10 m; no es cota de obra confirmada. | Contornos y sección documentados por el fabricante | 1 | 1 | Material: Hormigón HA-30
Cimentación de soporte de tuberías C07 · pedestal de hormigón | Parcela industrial Jinhong | Cimentación industrial | Cimentaciones de equipos y pedestales del fabricante · revisión recibida 04/09/2026 | 0.507098 | 0.507098 | 0.8 | 1.845 | 0.162 | process_plant | Zona de separación de aire | {"name":"Hormigón HA-30","status":"documentado","source":"Nota general de pedestales 2CED5"} | {"documented":[{"label":"Extensión local X","value":0.45,"unit":"m","source":"2CC5C, 2CD44, 2CC60, 2CC68, 2CC24, 2CC2B, 2CD69, 2CEAD, 2CE88","status":"derivada del contorno CAD"},{"label":"Extensión local Y","value":0.45,"unit":"m","source":"2CC5C, 2CD44, 2CC60, 2CC68, 2CC24, 2CC2B, 2CD69, 2CEAD, 2CE88","status":"derivada del contorno CAD"},{"label":"Cota inferior relativa adoptada","value":-0.6,"unit":"m","source":"ZD1 / DZ-1","status":"documentada"},{"label":"Cota superior relativa adoptada","value":0.2,"unit":"m","source":"ZD1 / DZ-1","status":"documentada / separación por material"}],"geometry":[{"label":"Extensión de la malla en X","value":0.5070979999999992,"unit":"m","source":"Geometría releída del IFC; datum absoluto de proceso provisional","status":"derivado"},{"label":"Extensión de la malla en Y","value":0.5070979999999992,"unit":"m","source":"Geometría releída del IFC; datum absoluto de proceso provisional","status":"derivado"},{"label":"Extensión de la malla en Z","value":0.8,"unit":"m","source":"Geometría releída del IFC; datum absoluto de proceso provisional","status":"derivado"},{"label":"Cota inferior de visualización","value":285.5,"unit":"m","source":"Geometría releída del IFC; datum absoluto de proceso provisional","status":"derivado"},{"label":"Cota superior de visualización","value":286.3,"unit":"m","source":"Geometría releída del IFC; datum absoluto de proceso provisional","status":"derivado"}]} | {"documentId":"LHD2609-JG00100-20260904","title":"Cimentaciones de equipos y pedestales del fabricante · revisión recibida 04/09/2026","date":"2026-09-04","sheet":"ZD1 / DZ-1","fileName":"LHD2609-JG00100_20260904.dwg","revisionCaveat":"Fecha de revisión tomada del nombre recibido; cajetines internos mantienen 02/07/2026 y algunos textos de plantilla.","sourceFileSha256":"b42eb027b7bc0b14c38d1d13514f4899b58a732aa8d0ba2ccf10fa2fc3192890"} | provisional | [] | {"Cota inferior relativa (m)":-0.6,"Cota superior relativa (m)":0.2,"Cero absoluto de visualización (m)":286.1,"Estado del cero absoluto":"Provisional","Criterio":"Las cotas relativas proceden del dibujo; la equivalencia absoluta no está confirmada."} | {"boundingBoxM":{"min":[45.697731,74.550523,0.5],"max":[46.204829,75.057621,1.3]},"extentsM":[0.507098,0.507098,0.8],"meshSurfaceM2":1.844999,"meshVolumeM3":0.162,"closedSolid":true,"basis":"Magnitudes de las mallas representadas, no cantidades certificadas de obra, compra o fabricación. Las partes pueden compartir superficies; no se suman como un despiece de materiales."} | {"profileId":"concrete_ha30","name":"Hormigón HA-30","materialName":"Hormigón HA-30","physicalMaterialStatus":"documentado","physicalMaterialSource":"Nota general de pedestales 2CED5","appearanceStatus":"criterio_visual","appearanceBasis":"Interpretación visual del material documental; el acabado, tono y parámetros PBR no son una especificación contractual.","note":"La apariencia gráfica no modifica ni confirma la especificación física del material."} | {"elementId":"found_0904_18b2cc5e6c81c8","ifcGuid":"1DeIuv$GXLjgsWZse7sbnM","ifcClass":"IfcFooting","buildingId":"process_plant","buildingName":"Zona de separación de aire","sourceDocumentId":"LHD2609-JG00100-20260904","sourceRepresentationKind":"foundation"} | {"layerId":"foundations","layerName":"Cimentaciones","role":"Cimentación industrial","basis":"Clasificación por función del elemento; no modifica las especificaciones documentales."} | {"profileId":"concrete_ha30","name":"Hormigón HA-30","status":"criterio_visual","basis":"Interpretación visual del material documental; el acabado, tono y parámetros PBR no son una especificación contractual.","physicalMaterialUnchanged":true} | 0.162 | Hormigón HA-30 | Hormigón HA-30 | found_0904_18b2cc5e6c81c8 | Nota general de pedestales 2CED5 | documentado | concrete_ha30 | [0.658824,0.658824,0.623529] | 0.94 | Zona de separación de aire; BIM · Cimentaciones | 0.507098 | 0.507098 | 0.8 | 285.5 | 286.3 | SUP-C07 | [] | ["C07"] | ZD1 / DZ-1 | ["2CC5C","2CD44","2CC60","2CC68","2CC24","2CC2B","2CD69","2CEAD","2CE88"] | SUP-C07/Cimentación de soporte de tuberías C07 · pedestal de hormigón | foundation | Geometría de fabricante; implantación absoluta provisional |  | Cimentaciones de equipos y pedestales del fabricante · revisión recibida 04/09/2026 | 2CC5C, 2CD44, 2CC60, 2CC68, 2CC24, 2CC2B, 2CD69, 2CEAD, 2CE88 | -0.6 | 0.2 | 0.2025 | Cotas relativas del dibujo. La equivalencia con un datum absoluto está pendiente. | Z del modelo = cota relativa + 1,10 m. Correspondencia provisional con 286,10 m; no es cota de obra confirmada. | Contornos y sección documentados por el fabricante | 0.45 | 0.45 | Material: Hormigón HA-30
Cimentación de soporte de tuberías C08 · cuerpo de hormigón | Parcela industrial Jinhong | Cimentación industrial | Cimentaciones de equipos y pedestales del fabricante · revisión recibida 04/09/2026 | 1.12689 | 1.12689 | 0.4 | 3.6 | 0.4 | process_plant | Zona de separación de aire | {"name":"Hormigón HA-30","status":"documentado","source":"Nota general de pedestales 2CED5"} | {"documented":[{"label":"Extensión local X","value":1.0,"unit":"m","source":"2CC5D, 2CD45, 2CC61, 2CC69, 2CC25, 2CC2C, 2CD6A, 2CEAE, 2CE89","status":"derivada del contorno CAD"},{"label":"Extensión local Y","value":1.0,"unit":"m","source":"2CC5D, 2CD45, 2CC61, 2CC69, 2CC25, 2CC2C, 2CD6A, 2CEAE, 2CE89","status":"derivada del contorno CAD"},{"label":"Cota inferior relativa adoptada","value":-1.0,"unit":"m","source":"ZD1 / DZ-1","status":"documentada"},{"label":"Cota superior relativa adoptada","value":-0.6,"unit":"m","source":"ZD1 / DZ-1","status":"documentada / separación por material"}],"geometry":[{"label":"Extensión de la malla en X","value":1.1268850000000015,"unit":"m","source":"Geometría releída del IFC; datum absoluto de proceso provisional","status":"derivado"},{"label":"Extensión de la malla en Y","value":1.1268850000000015,"unit":"m","source":"Geometría releída del IFC; datum absoluto de proceso provisional","status":"derivado"},{"label":"Extensión de la malla en Z","value":0.4,"unit":"m","source":"Geometría releída del IFC; datum absoluto de proceso provisional","status":"derivado"},{"label":"Cota inferior de visualización","value":285.1,"unit":"m","source":"Geometría releída del IFC; datum absoluto de proceso provisional","status":"derivado"},{"label":"Cota superior de visualización","value":285.5,"unit":"m","source":"Geometría releída del IFC; datum absoluto de proceso provisional","status":"derivado"}]} | {"documentId":"LHD2609-JG00100-20260904","title":"Cimentaciones de equipos y pedestales del fabricante · revisión recibida 04/09/2026","date":"2026-09-04","sheet":"ZD1 / DZ-1","fileName":"LHD2609-JG00100_20260904.dwg","revisionCaveat":"Fecha de revisión tomada del nombre recibido; cajetines internos mantienen 02/07/2026 y algunos textos de plantilla.","sourceFileSha256":"b42eb027b7bc0b14c38d1d13514f4899b58a732aa8d0ba2ccf10fa2fc3192890"} | provisional | [] | {"Cota inferior relativa (m)":-1.0,"Cota superior relativa (m)":-0.6,"Cero absoluto de visualización (m)":286.1,"Estado del cero absoluto":"Provisional","Criterio":"Las cotas relativas proceden del dibujo; la equivalencia absoluta no está confirmada."} | {"boundingBoxM":{"min":[46.52712,74.083995,0.1],"max":[47.654005,75.21088,0.5]},"extentsM":[1.126885,1.126885,0.4],"meshSurfaceM2":3.600001,"meshVolumeM3":0.4,"closedSolid":true,"basis":"Magnitudes de las mallas representadas, no cantidades certificadas de obra, compra o fabricación. Las partes pueden compartir superficies; no se suman como un despiece de materiales."} | {"profileId":"concrete_ha30","name":"Hormigón HA-30","materialName":"Hormigón HA-30","physicalMaterialStatus":"documentado","physicalMaterialSource":"Nota general de pedestales 2CED5","appearanceStatus":"criterio_visual","appearanceBasis":"Interpretación visual del material documental; el acabado, tono y parámetros PBR no son una especificación contractual.","note":"La apariencia gráfica no modifica ni confirma la especificación física del material."} | {"elementId":"found_0904_7f778d5cc769e0","ifcGuid":"3JdfN57IjKFwMdETxd9NV$","ifcClass":"IfcFooting","buildingId":"process_plant","buildingName":"Zona de separación de aire","sourceDocumentId":"LHD2609-JG00100-20260904","sourceRepresentationKind":"foundation"} | {"layerId":"foundations","layerName":"Cimentaciones","role":"Cimentación industrial","basis":"Clasificación por función del elemento; no modifica las especificaciones documentales."} | {"profileId":"concrete_ha30","name":"Hormigón HA-30","status":"criterio_visual","basis":"Interpretación visual del material documental; el acabado, tono y parámetros PBR no son una especificación contractual.","physicalMaterialUnchanged":true} | 0.4 | Hormigón HA-30 | Hormigón HA-30 | found_0904_7f778d5cc769e0 | Nota general de pedestales 2CED5 | documentado | concrete_ha30 | [0.658824,0.658824,0.623529] | 0.94 | Zona de separación de aire; BIM · Cimentaciones | 1.12689 | 1.12689 | 0.4 | 285.1 | 285.5 | SUP-C08 | [] | ["C08"] | ZD1 / DZ-1 | ["2CC5D","2CD45","2CC61","2CC69","2CC25","2CC2C","2CD6A","2CEAE","2CE89"] | SUP-C08/Cimentación de soporte de tuberías C08 · cuerpo de hormigón | foundation | Geometría de fabricante; implantación absoluta provisional |  | Cimentaciones de equipos y pedestales del fabricante · revisión recibida 04/09/2026 | 2CC5D, 2CD45, 2CC61, 2CC69, 2CC25, 2CC2C, 2CD6A, 2CEAE, 2CE89 | -1 | -0.6 | 1 | Cotas relativas del dibujo. La equivalencia con un datum absoluto está pendiente. | Z del modelo = cota relativa + 1,10 m. Correspondencia provisional con 286,10 m; no es cota de obra confirmada. | Contornos y sección documentados por el fabricante | 1 | 1 | Material: Hormigón HA-30
Cimentación de soporte de tuberías C08 · pedestal de hormigón | Parcela industrial Jinhong | Cimentación industrial | Cimentaciones de equipos y pedestales del fabricante · revisión recibida 04/09/2026 | 0.507098 | 0.507098 | 0.8 | 1.845 | 0.162 | process_plant | Zona de separación de aire | {"name":"Hormigón HA-30","status":"documentado","source":"Nota general de pedestales 2CED5"} | {"documented":[{"label":"Extensión local X","value":0.45,"unit":"m","source":"2CC5D, 2CD45, 2CC61, 2CC69, 2CC25, 2CC2C, 2CD6A, 2CEAE, 2CE89","status":"derivada del contorno CAD"},{"label":"Extensión local Y","value":0.45,"unit":"m","source":"2CC5D, 2CD45, 2CC61, 2CC69, 2CC25, 2CC2C, 2CD6A, 2CEAE, 2CE89","status":"derivada del contorno CAD"},{"label":"Cota inferior relativa adoptada","value":-0.6,"unit":"m","source":"ZD1 / DZ-1","status":"documentada"},{"label":"Cota superior relativa adoptada","value":0.2,"unit":"m","source":"ZD1 / DZ-1","status":"documentada / separación por material"}],"geometry":[{"label":"Extensión de la malla en X","value":0.5070979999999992,"unit":"m","source":"Geometría releída del IFC; datum absoluto de proceso provisional","status":"derivado"},{"label":"Extensión de la malla en Y","value":0.5070979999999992,"unit":"m","source":"Geometría releída del IFC; datum absoluto de proceso provisional","status":"derivado"},{"label":"Extensión de la malla en Z","value":0.8,"unit":"m","source":"Geometría releída del IFC; datum absoluto de proceso provisional","status":"derivado"},{"label":"Cota inferior de visualización","value":285.5,"unit":"m","source":"Geometría releída del IFC; datum absoluto de proceso provisional","status":"derivado"},{"label":"Cota superior de visualización","value":286.3,"unit":"m","source":"Geometría releída del IFC; datum absoluto de proceso provisional","status":"derivado"}]} | {"documentId":"LHD2609-JG00100-20260904","title":"Cimentaciones de equipos y pedestales del fabricante · revisión recibida 04/09/2026","date":"2026-09-04","sheet":"ZD1 / DZ-1","fileName":"LHD2609-JG00100_20260904.dwg","revisionCaveat":"Fecha de revisión tomada del nombre recibido; cajetines internos mantienen 02/07/2026 y algunos textos de plantilla.","sourceFileSha256":"b42eb027b7bc0b14c38d1d13514f4899b58a732aa8d0ba2ccf10fa2fc3192890"} | provisional | [] | {"Cota inferior relativa (m)":-0.6,"Cota superior relativa (m)":0.2,"Cero absoluto de visualización (m)":286.1,"Estado del cero absoluto":"Provisional","Criterio":"Las cotas relativas proceden del dibujo; la equivalencia absoluta no está confirmada."} | {"boundingBoxM":{"min":[46.837014,74.393889,0.5],"max":[47.344112,74.900987,1.3]},"extentsM":[0.507098,0.507098,0.8],"meshSurfaceM2":1.845,"meshVolumeM3":0.162,"closedSolid":true,"basis":"Magnitudes de las mallas representadas, no cantidades certificadas de obra, compra o fabricación. Las partes pueden compartir superficies; no se suman como un despiece de materiales."} | {"profileId":"concrete_ha30","name":"Hormigón HA-30","materialName":"Hormigón HA-30","physicalMaterialStatus":"documentado","physicalMaterialSource":"Nota general de pedestales 2CED5","appearanceStatus":"criterio_visual","appearanceBasis":"Interpretación visual del material documental; el acabado, tono y parámetros PBR no son una especificación contractual.","note":"La apariencia gráfica no modifica ni confirma la especificación física del material."} | {"elementId":"found_0904_655890066b3b9e","ifcGuid":"3A1_8tWDjSWOaij7nT$nWt","ifcClass":"IfcFooting","buildingId":"process_plant","buildingName":"Zona de separación de aire","sourceDocumentId":"LHD2609-JG00100-20260904","sourceRepresentationKind":"foundation"} | {"layerId":"foundations","layerName":"Cimentaciones","role":"Cimentación industrial","basis":"Clasificación por función del elemento; no modifica las especificaciones documentales."} | {"profileId":"concrete_ha30","name":"Hormigón HA-30","status":"criterio_visual","basis":"Interpretación visual del material documental; el acabado, tono y parámetros PBR no son una especificación contractual.","physicalMaterialUnchanged":true} | 0.162 | Hormigón HA-30 | Hormigón HA-30 | found_0904_655890066b3b9e | Nota general de pedestales 2CED5 | documentado | concrete_ha30 | [0.658824,0.658824,0.623529] | 0.94 | Zona de separación de aire; BIM · Cimentaciones | 0.507098 | 0.507098 | 0.8 | 285.5 | 286.3 | SUP-C08 | [] | ["C08"] | ZD1 / DZ-1 | ["2CC5D","2CD45","2CC61","2CC69","2CC25","2CC2C","2CD6A","2CEAE","2CE89"] | SUP-C08/Cimentación de soporte de tuberías C08 · pedestal de hormigón | foundation | Geometría de fabricante; implantación absoluta provisional |  | Cimentaciones de equipos y pedestales del fabricante · revisión recibida 04/09/2026 | 2CC5D, 2CD45, 2CC61, 2CC69, 2CC25, 2CC2C, 2CD6A, 2CEAE, 2CE89 | -0.6 | 0.2 | 0.2025 | Cotas relativas del dibujo. La equivalencia con un datum absoluto está pendiente. | Z del modelo = cota relativa + 1,10 m. Correspondencia provisional con 286,10 m; no es cota de obra confirmada. | Contornos y sección documentados por el fabricante | 0.45 | 0.45 | Material: Hormigón HA-30
Cimentación de soporte de tuberías C09 · cuerpo de hormigón | Parcela industrial Jinhong | Cimentación industrial | Cimentaciones de equipos y pedestales del fabricante · revisión recibida 04/09/2026 | 1.12688 | 1.12688 | 0.4 | 3.59999 | 0.399999 | process_plant | Zona de separación de aire | {"name":"Hormigón HA-30","status":"documentado","source":"Nota general de pedestales 2CED5"} | {"documented":[{"label":"Extensión local X","value":1.0,"unit":"m","source":"2CC5E, 2CD46, 2CDAA, 2CC6A, 2CC26, 2CC2D, 2CD6B, 2CEAF, 2CE8A","status":"derivada del contorno CAD"},{"label":"Extensión local Y","value":1.0,"unit":"m","source":"2CC5E, 2CD46, 2CDAA, 2CC6A, 2CC26, 2CC2D, 2CD6B, 2CEAF, 2CE8A","status":"derivada del contorno CAD"},{"label":"Cota inferior relativa adoptada","value":-1.0,"unit":"m","source":"ZD1 / DZ-1","status":"documentada"},{"label":"Cota superior relativa adoptada","value":-0.6,"unit":"m","source":"ZD1 / DZ-1","status":"documentada / separación por material"}],"geometry":[{"label":"Extensión de la malla en X","value":1.126884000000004,"unit":"m","source":"Geometría releída del IFC; datum absoluto de proceso provisional","status":"derivado"},{"label":"Extensión de la malla en Y","value":1.1268839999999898,"unit":"m","source":"Geometría releída del IFC; datum absoluto de proceso provisional","status":"derivado"},{"label":"Extensión de la malla en Z","value":0.4,"unit":"m","source":"Geometría releída del IFC; datum absoluto de proceso provisional","status":"derivado"},{"label":"Cota inferior de visualización","value":285.1,"unit":"m","source":"Geometría releída del IFC; datum absoluto de proceso provisional","status":"derivado"},{"label":"Cota superior de visualización","value":285.5,"unit":"m","source":"Geometría releída del IFC; datum absoluto de proceso provisional","status":"derivado"}]} | {"documentId":"LHD2609-JG00100-20260904","title":"Cimentaciones de equipos y pedestales del fabricante · revisión recibida 04/09/2026","date":"2026-09-04","sheet":"ZD1 / DZ-1","fileName":"LHD2609-JG00100_20260904.dwg","revisionCaveat":"Fecha de revisión tomada del nombre recibido; cajetines internos mantienen 02/07/2026 y algunos textos de plantilla.","sourceFileSha256":"b42eb027b7bc0b14c38d1d13514f4899b58a732aa8d0ba2ccf10fa2fc3192890"} | provisional | [] | {"Cota inferior relativa (m)":-1.0,"Cota superior relativa (m)":-0.6,"Cero absoluto de visualización (m)":286.1,"Estado del cero absoluto":"Provisional","Criterio":"Las cotas relativas proceden del dibujo; la equivalencia absoluta no está confirmada."} | {"boundingBoxM":{"min":[44.706818,69.287226,0.1],"max":[45.833702,70.41411,0.5]},"extentsM":[1.126884,1.126884,0.4],"meshSurfaceM2":3.599995,"meshVolumeM3":0.399999,"closedSolid":true,"basis":"Magnitudes de las mallas representadas, no cantidades certificadas de obra, compra o fabricación. Las partes pueden compartir superficies; no se suman como un despiece de materiales."} | {"profileId":"concrete_ha30","name":"Hormigón HA-30","materialName":"Hormigón HA-30","physicalMaterialStatus":"documentado","physicalMaterialSource":"Nota general de pedestales 2CED5","appearanceStatus":"criterio_visual","appearanceBasis":"Interpretación visual del material documental; el acabado, tono y parámetros PBR no son una especificación contractual.","note":"La apariencia gráfica no modifica ni confirma la especificación física del material."} | {"elementId":"found_0904_be891c0b7b3e95","ifcGuid":"3NxeRyfFnGmQ3PeCMuQ0c4","ifcClass":"IfcFooting","buildingId":"process_plant","buildingName":"Zona de separación de aire","sourceDocumentId":"LHD2609-JG00100-20260904","sourceRepresentationKind":"foundation"} | {"layerId":"foundations","layerName":"Cimentaciones","role":"Cimentación industrial","basis":"Clasificación por función del elemento; no modifica las especificaciones documentales."} | {"profileId":"concrete_ha30","name":"Hormigón HA-30","status":"criterio_visual","basis":"Interpretación visual del material documental; el acabado, tono y parámetros PBR no son una especificación contractual.","physicalMaterialUnchanged":true} | 0.4 | Hormigón HA-30 | Hormigón HA-30 | found_0904_be891c0b7b3e95 | Nota general de pedestales 2CED5 | documentado | concrete_ha30 | [0.658824,0.658824,0.623529] | 0.94 | Zona de separación de aire; BIM · Cimentaciones | 1.12688 | 1.12688 | 0.4 | 285.1 | 285.5 | SUP-C09 | [] | ["C09"] | ZD1 / DZ-1 | ["2CC5E","2CD46","2CDAA","2CC6A","2CC26","2CC2D","2CD6B","2CEAF","2CE8A"] | SUP-C09/Cimentación de soporte de tuberías C09 · cuerpo de hormigón | foundation | Geometría de fabricante; implantación absoluta provisional |  | Cimentaciones de equipos y pedestales del fabricante · revisión recibida 04/09/2026 | 2CC5E, 2CD46, 2CDAA, 2CC6A, 2CC26, 2CC2D, 2CD6B, 2CEAF, 2CE8A | -1 | -0.6 | 1 | Cotas relativas del dibujo. La equivalencia con un datum absoluto está pendiente. | Z del modelo = cota relativa + 1,10 m. Correspondencia provisional con 286,10 m; no es cota de obra confirmada. | Contornos y sección documentados por el fabricante | 1 | 1 | Material: Hormigón HA-30
Cimentación de soporte de tuberías C09 · pedestal de hormigón | Parcela industrial Jinhong | Cimentación industrial | Cimentaciones de equipos y pedestales del fabricante · revisión recibida 04/09/2026 | 0.507098 | 0.507098 | 0.8 | 1.845 | 0.162 | process_plant | Zona de separación de aire | {"name":"Hormigón HA-30","status":"documentado","source":"Nota general de pedestales 2CED5"} | {"documented":[{"label":"Extensión local X","value":0.45,"unit":"m","source":"2CC5E, 2CD46, 2CDAA, 2CC6A, 2CC26, 2CC2D, 2CD6B, 2CEAF, 2CE8A","status":"derivada del contorno CAD"},{"label":"Extensión local Y","value":0.45,"unit":"m","source":"2CC5E, 2CD46, 2CDAA, 2CC6A, 2CC26, 2CC2D, 2CD6B, 2CEAF, 2CE8A","status":"derivada del contorno CAD"},{"label":"Cota inferior relativa adoptada","value":-0.6,"unit":"m","source":"ZD1 / DZ-1","status":"documentada"},{"label":"Cota superior relativa adoptada","value":0.2,"unit":"m","source":"ZD1 / DZ-1","status":"documentada / separación por material"}],"geometry":[{"label":"Extensión de la malla en X","value":0.5070979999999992,"unit":"m","source":"Geometría releída del IFC; datum absoluto de proceso provisional","status":"derivado"},{"label":"Extensión de la malla en Y","value":0.5070979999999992,"unit":"m","source":"Geometría releída del IFC; datum absoluto de proceso provisional","status":"derivado"},{"label":"Extensión de la malla en Z","value":0.8,"unit":"m","source":"Geometría releída del IFC; datum absoluto de proceso provisional","status":"derivado"},{"label":"Cota inferior de visualización","value":285.5,"unit":"m","source":"Geometría releída del IFC; datum absoluto de proceso provisional","status":"derivado"},{"label":"Cota superior de visualización","value":286.3,"unit":"m","source":"Geometría releída del IFC; datum absoluto de proceso provisional","status":"derivado"}]} | {"documentId":"LHD2609-JG00100-20260904","title":"Cimentaciones de equipos y pedestales del fabricante · revisión recibida 04/09/2026","date":"2026-09-04","sheet":"ZD1 / DZ-1","fileName":"LHD2609-JG00100_20260904.dwg","revisionCaveat":"Fecha de revisión tomada del nombre recibido; cajetines internos mantienen 02/07/2026 y algunos textos de plantilla.","sourceFileSha256":"b42eb027b7bc0b14c38d1d13514f4899b58a732aa8d0ba2ccf10fa2fc3192890"} | provisional | [] | {"Cota inferior relativa (m)":-0.6,"Cota superior relativa (m)":0.2,"Cero absoluto de visualización (m)":286.1,"Estado del cero absoluto":"Provisional","Criterio":"Las cotas relativas proceden del dibujo; la equivalencia absoluta no está confirmada."} | {"boundingBoxM":{"min":[45.016711,69.597119,0.5],"max":[45.523809,70.104217,1.3]},"extentsM":[0.507098,0.507098,0.8],"meshSurfaceM2":1.844998,"meshVolumeM3":0.162,"closedSolid":true,"basis":"Magnitudes de las mallas representadas, no cantidades certificadas de obra, compra o fabricación. Las partes pueden compartir superficies; no se suman como un despiece de materiales."} | {"profileId":"concrete_ha30","name":"Hormigón HA-30","materialName":"Hormigón HA-30","physicalMaterialStatus":"documentado","physicalMaterialSource":"Nota general de pedestales 2CED5","appearanceStatus":"criterio_visual","appearanceBasis":"Interpretación visual del material documental; el acabado, tono y parámetros PBR no son una especificación contractual.","note":"La apariencia gráfica no modifica ni confirma la especificación física del material."} | {"elementId":"found_0904_c13696c25f5b59","ifcGuid":"3qbc1VhBjSLwM23AjXzSoY","ifcClass":"IfcFooting","buildingId":"process_plant","buildingName":"Zona de separación de aire","sourceDocumentId":"LHD2609-JG00100-20260904","sourceRepresentationKind":"foundation"} | {"layerId":"foundations","layerName":"Cimentaciones","role":"Cimentación industrial","basis":"Clasificación por función del elemento; no modifica las especificaciones documentales."} | {"profileId":"concrete_ha30","name":"Hormigón HA-30","status":"criterio_visual","basis":"Interpretación visual del material documental; el acabado, tono y parámetros PBR no son una especificación contractual.","physicalMaterialUnchanged":true} | 0.162 | Hormigón HA-30 | Hormigón HA-30 | found_0904_c13696c25f5b59 | Nota general de pedestales 2CED5 | documentado | concrete_ha30 | [0.658824,0.658824,0.623529] | 0.94 | Zona de separación de aire; BIM · Cimentaciones | 0.507098 | 0.507098 | 0.8 | 285.5 | 286.3 | SUP-C09 | [] | ["C09"] | ZD1 / DZ-1 | ["2CC5E","2CD46","2CDAA","2CC6A","2CC26","2CC2D","2CD6B","2CEAF","2CE8A"] | SUP-C09/Cimentación de soporte de tuberías C09 · pedestal de hormigón | foundation | Geometría de fabricante; implantación absoluta provisional |  | Cimentaciones de equipos y pedestales del fabricante · revisión recibida 04/09/2026 | 2CC5E, 2CD46, 2CDAA, 2CC6A, 2CC26, 2CC2D, 2CD6B, 2CEAF, 2CE8A | -0.6 | 0.2 | 0.2025 | Cotas relativas del dibujo. La equivalencia con un datum absoluto está pendiente. | Z del modelo = cota relativa + 1,10 m. Correspondencia provisional con 286,10 m; no es cota de obra confirmada. | Contornos y sección documentados por el fabricante | 0.45 | 0.45 | Material: Hormigón HA-30
Cimentación de soporte de tuberías C10 · cuerpo de hormigón | Parcela industrial Jinhong | Cimentación industrial | Cimentaciones de equipos y pedestales del fabricante · revisión recibida 04/09/2026 | 1.12688 | 1.12689 | 0.4 | 3.6 | 0.4 | process_plant | Zona de separación de aire | {"name":"Hormigón HA-30","status":"documentado","source":"Nota general de pedestales 2CED5"} | {"documented":[{"label":"Extensión local X","value":1.0,"unit":"m","source":"2CC5F, 2CD47, 2CDAB, 2CC6B, 2CC27, 2CC2E, 2CD6C, 2CEB0, 2CE8B","status":"derivada del contorno CAD"},{"label":"Extensión local Y","value":1.0,"unit":"m","source":"2CC5F, 2CD47, 2CDAB, 2CC6B, 2CC27, 2CC2E, 2CD6C, 2CEB0, 2CE8B","status":"derivada del contorno CAD"},{"label":"Cota inferior relativa adoptada","value":-1.0,"unit":"m","source":"ZD1 / DZ-1","status":"documentada"},{"label":"Cota superior relativa adoptada","value":-0.6,"unit":"m","source":"ZD1 / DZ-1","status":"documentada / separación por material"}],"geometry":[{"label":"Extensión de la malla en X","value":1.126884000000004,"unit":"m","source":"Geometría releída del IFC; datum absoluto de proceso provisional","status":"derivado"},{"label":"Extensión de la malla en Y","value":1.1268850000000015,"unit":"m","source":"Geometría releída del IFC; datum absoluto de proceso provisional","status":"derivado"},{"label":"Extensión de la malla en Z","value":0.4,"unit":"m","source":"Geometría releída del IFC; datum absoluto de proceso provisional","status":"derivado"},{"label":"Cota inferior de visualización","value":285.1,"unit":"m","source":"Geometría releída del IFC; datum absoluto de proceso provisional","status":"derivado"},{"label":"Cota superior de visualización","value":285.5,"unit":"m","source":"Geometría releída del IFC; datum absoluto de proceso provisional","status":"derivado"}]} | {"documentId":"LHD2609-JG00100-20260904","title":"Cimentaciones de equipos y pedestales del fabricante · revisión recibida 04/09/2026","date":"2026-09-04","sheet":"ZD1 / DZ-1","fileName":"LHD2609-JG00100_20260904.dwg","revisionCaveat":"Fecha de revisión tomada del nombre recibido; cajetines internos mantienen 02/07/2026 y algunos textos de plantilla.","sourceFileSha256":"b42eb027b7bc0b14c38d1d13514f4899b58a732aa8d0ba2ccf10fa2fc3192890"} | provisional | [] | {"Cota inferior relativa (m)":-1.0,"Cota superior relativa (m)":-0.6,"Cero absoluto de visualización (m)":286.1,"Estado del cero absoluto":"Provisional","Criterio":"Las cotas relativas proceden del dibujo; la equivalencia absoluta no está confirmada."} | {"boundingBoxM":{"min":[45.846101,69.130591,0.1],"max":[46.972985,70.257476,0.5]},"extentsM":[1.126884,1.126885,0.4],"meshSurfaceM2":3.599998,"meshVolumeM3":0.4,"closedSolid":true,"basis":"Magnitudes de las mallas representadas, no cantidades certificadas de obra, compra o fabricación. Las partes pueden compartir superficies; no se suman como un despiece de materiales."} | {"profileId":"concrete_ha30","name":"Hormigón HA-30","materialName":"Hormigón HA-30","physicalMaterialStatus":"documentado","physicalMaterialSource":"Nota general de pedestales 2CED5","appearanceStatus":"criterio_visual","appearanceBasis":"Interpretación visual del material documental; el acabado, tono y parámetros PBR no son una especificación contractual.","note":"La apariencia gráfica no modifica ni confirma la especificación física del material."} | {"elementId":"found_0904_de344a9322909b","ifcGuid":"1R$uLRU7PMjfL3X2Ycd5$J","ifcClass":"IfcFooting","buildingId":"process_plant","buildingName":"Zona de separación de aire","sourceDocumentId":"LHD2609-JG00100-20260904","sourceRepresentationKind":"foundation"} | {"layerId":"foundations","layerName":"Cimentaciones","role":"Cimentación industrial","basis":"Clasificación por función del elemento; no modifica las especificaciones documentales."} | {"profileId":"concrete_ha30","name":"Hormigón HA-30","status":"criterio_visual","basis":"Interpretación visual del material documental; el acabado, tono y parámetros PBR no son una especificación contractual.","physicalMaterialUnchanged":true} | 0.4 | Hormigón HA-30 | Hormigón HA-30 | found_0904_de344a9322909b | Nota general de pedestales 2CED5 | documentado | concrete_ha30 | [0.658824,0.658824,0.623529] | 0.94 | Zona de separación de aire; BIM · Cimentaciones | 1.12688 | 1.12689 | 0.4 | 285.1 | 285.5 | SUP-C10 | [] | ["C10"] | ZD1 / DZ-1 | ["2CC5F","2CD47","2CDAB","2CC6B","2CC27","2CC2E","2CD6C","2CEB0","2CE8B"] | SUP-C10/Cimentación de soporte de tuberías C10 · cuerpo de hormigón | foundation | Geometría de fabricante; implantación absoluta provisional |  | Cimentaciones de equipos y pedestales del fabricante · revisión recibida 04/09/2026 | 2CC5F, 2CD47, 2CDAB, 2CC6B, 2CC27, 2CC2E, 2CD6C, 2CEB0, 2CE8B | -1 | -0.6 | 1 | Cotas relativas del dibujo. La equivalencia con un datum absoluto está pendiente. | Z del modelo = cota relativa + 1,10 m. Correspondencia provisional con 286,10 m; no es cota de obra confirmada. | Contornos y sección documentados por el fabricante | 1 | 1 | Material: Hormigón HA-30
Cimentación de soporte de tuberías C10 · pedestal de hormigón | Parcela industrial Jinhong | Cimentación industrial | Cimentaciones de equipos y pedestales del fabricante · revisión recibida 04/09/2026 | 0.507098 | 0.507099 | 0.8 | 1.845 | 0.162 | process_plant | Zona de separación de aire | {"name":"Hormigón HA-30","status":"documentado","source":"Nota general de pedestales 2CED5"} | {"documented":[{"label":"Extensión local X","value":0.45,"unit":"m","source":"2CC5F, 2CD47, 2CDAB, 2CC6B, 2CC27, 2CC2E, 2CD6C, 2CEB0, 2CE8B","status":"derivada del contorno CAD"},{"label":"Extensión local Y","value":0.45,"unit":"m","source":"2CC5F, 2CD47, 2CDAB, 2CC6B, 2CC27, 2CC2E, 2CD6C, 2CEB0, 2CE8B","status":"derivada del contorno CAD"},{"label":"Cota inferior relativa adoptada","value":-0.6,"unit":"m","source":"ZD1 / DZ-1","status":"documentada"},{"label":"Cota superior relativa adoptada","value":0.2,"unit":"m","source":"ZD1 / DZ-1","status":"documentada / separación por material"}],"geometry":[{"label":"Extensión de la malla en X","value":0.5070979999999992,"unit":"m","source":"Geometría releída del IFC; datum absoluto de proceso provisional","status":"derivado"},{"label":"Extensión de la malla en Y","value":0.5070989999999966,"unit":"m","source":"Geometría releída del IFC; datum absoluto de proceso provisional","status":"derivado"},{"label":"Extensión de la malla en Z","value":0.8,"unit":"m","source":"Geometría releída del IFC; datum absoluto de proceso provisional","status":"derivado"},{"label":"Cota inferior de visualización","value":285.5,"unit":"m","source":"Geometría releída del IFC; datum absoluto de proceso provisional","status":"derivado"},{"label":"Cota superior de visualización","value":286.3,"unit":"m","source":"Geometría releída del IFC; datum absoluto de proceso provisional","status":"derivado"}]} | {"documentId":"LHD2609-JG00100-20260904","title":"Cimentaciones de equipos y pedestales del fabricante · revisión recibida 04/09/2026","date":"2026-09-04","sheet":"ZD1 / DZ-1","fileName":"LHD2609-JG00100_20260904.dwg","revisionCaveat":"Fecha de revisión tomada del nombre recibido; cajetines internos mantienen 02/07/2026 y algunos textos de plantilla.","sourceFileSha256":"b42eb027b7bc0b14c38d1d13514f4899b58a732aa8d0ba2ccf10fa2fc3192890"} | provisional | [] | {"Cota inferior relativa (m)":-0.6,"Cota superior relativa (m)":0.2,"Cero absoluto de visualización (m)":286.1,"Estado del cero absoluto":"Provisional","Criterio":"Las cotas relativas proceden del dibujo; la equivalencia absoluta no está confirmada."} | {"boundingBoxM":{"min":[46.155994,69.440484,0.5],"max":[46.663092,69.947583,1.3]},"extentsM":[0.507098,0.507099,0.8],"meshSurfaceM2":1.845001,"meshVolumeM3":0.162,"closedSolid":true,"basis":"Magnitudes de las mallas representadas, no cantidades certificadas de obra, compra o fabricación. Las partes pueden compartir superficies; no se suman como un despiece de materiales."} | {"profileId":"concrete_ha30","name":"Hormigón HA-30","materialName":"Hormigón HA-30","physicalMaterialStatus":"documentado","physicalMaterialSource":"Nota general de pedestales 2CED5","appearanceStatus":"criterio_visual","appearanceBasis":"Interpretación visual del material documental; el acabado, tono y parámetros PBR no son una especificación contractual.","note":"La apariencia gráfica no modifica ni confirma la especificación física del material."} | {"elementId":"found_0904_c86c27c912fb89","ifcGuid":"38oQ1f03nHSQRliyrTZ08b","ifcClass":"IfcFooting","buildingId":"process_plant","buildingName":"Zona de separación de aire","sourceDocumentId":"LHD2609-JG00100-20260904","sourceRepresentationKind":"foundation"} | {"layerId":"foundations","layerName":"Cimentaciones","role":"Cimentación industrial","basis":"Clasificación por función del elemento; no modifica las especificaciones documentales."} | {"profileId":"concrete_ha30","name":"Hormigón HA-30","status":"criterio_visual","basis":"Interpretación visual del material documental; el acabado, tono y parámetros PBR no son una especificación contractual.","physicalMaterialUnchanged":true} | 0.162 | Hormigón HA-30 | Hormigón HA-30 | found_0904_c86c27c912fb89 | Nota general de pedestales 2CED5 | documentado | concrete_ha30 | [0.658824,0.658824,0.623529] | 0.94 | Zona de separación de aire; BIM · Cimentaciones | 0.507098 | 0.507099 | 0.8 | 285.5 | 286.3 | SUP-C10 | [] | ["C10"] | ZD1 / DZ-1 | ["2CC5F","2CD47","2CDAB","2CC6B","2CC27","2CC2E","2CD6C","2CEB0","2CE8B"] | SUP-C10/Cimentación de soporte de tuberías C10 · pedestal de hormigón | foundation | Geometría de fabricante; implantación absoluta provisional |  | Cimentaciones de equipos y pedestales del fabricante · revisión recibida 04/09/2026 | 2CC5F, 2CD47, 2CDAB, 2CC6B, 2CC27, 2CC2E, 2CD6C, 2CEB0, 2CE8B | -0.6 | 0.2 | 0.2025 | Cotas relativas del dibujo. La equivalencia con un datum absoluto está pendiente. | Z del modelo = cota relativa + 1,10 m. Correspondencia provisional con 286,10 m; no es cota de obra confirmada. | Contornos y sección documentados por el fabricante | 0.45 | 0.45 | Material: Hormigón HA-30
Cimentación de soporte de tuberías C11 · cuerpo de hormigón | Parcela industrial Jinhong | Cimentación industrial | Cimentaciones de equipos y pedestales del fabricante · revisión recibida 04/09/2026 | 1.12689 | 1.12688 | 0.4 | 3.6 | 0.4 | process_plant | Zona de separación de aire | {"name":"Hormigón HA-30","status":"documentado","source":"Nota general de pedestales 2CED5"} | {"documented":[{"label":"Extensión local X","value":1.0,"unit":"m","source":"2CC77, 2CD48, 2CDAC, 2CC78, 2CC73, 2CC74, 2CD6D, 2CEB1, 2CE8C","status":"derivada del contorno CAD"},{"label":"Extensión local Y","value":1.0,"unit":"m","source":"2CC77, 2CD48, 2CDAC, 2CC78, 2CC73, 2CC74, 2CD6D, 2CEB1, 2CE8C","status":"derivada del contorno CAD"},{"label":"Cota inferior relativa adoptada","value":-1.0,"unit":"m","source":"ZD1 / DZ-1","status":"documentada"},{"label":"Cota superior relativa adoptada","value":-0.6,"unit":"m","source":"ZD1 / DZ-1","status":"documentada / separación por material"}],"geometry":[{"label":"Extensión de la malla en X","value":1.1268850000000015,"unit":"m","source":"Geometría releída del IFC; datum absoluto de proceso provisional","status":"derivado"},{"label":"Extensión de la malla en Y","value":1.126884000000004,"unit":"m","source":"Geometría releída del IFC; datum absoluto de proceso provisional","status":"derivado"},{"label":"Extensión de la malla en Z","value":0.4,"unit":"m","source":"Geometría releída del IFC; datum absoluto de proceso provisional","status":"derivado"},{"label":"Cota inferior de visualización","value":285.1,"unit":"m","source":"Geometría releída del IFC; datum absoluto de proceso provisional","status":"derivado"},{"label":"Cota superior de visualización","value":285.5,"unit":"m","source":"Geometría releída del IFC; datum absoluto de proceso provisional","status":"derivado"}]} | {"documentId":"LHD2609-JG00100-20260904","title":"Cimentaciones de equipos y pedestales del fabricante · revisión recibida 04/09/2026","date":"2026-09-04","sheet":"ZD1 / DZ-1","fileName":"LHD2609-JG00100_20260904.dwg","revisionCaveat":"Fecha de revisión tomada del nombre recibido; cajetines internos mantienen 02/07/2026 y algunos textos de plantilla.","sourceFileSha256":"b42eb027b7bc0b14c38d1d13514f4899b58a732aa8d0ba2ccf10fa2fc3192890"} | provisional | [] | {"Cota inferior relativa (m)":-1.0,"Cota superior relativa (m)":-0.6,"Cero absoluto de visualización (m)":286.1,"Estado del cero absoluto":"Provisional","Criterio":"Las cotas relativas proceden del dibujo; la equivalencia absoluta no está confirmada."} | {"boundingBoxM":{"min":[44.025798,64.333822,0.1],"max":[45.152683,65.460706,0.5]},"extentsM":[1.126885,1.126884,0.4],"meshSurfaceM2":3.599999,"meshVolumeM3":0.4,"closedSolid":true,"basis":"Magnitudes de las mallas representadas, no cantidades certificadas de obra, compra o fabricación. Las partes pueden compartir superficies; no se suman como un despiece de materiales."} | {"profileId":"concrete_ha30","name":"Hormigón HA-30","materialName":"Hormigón HA-30","physicalMaterialStatus":"documentado","physicalMaterialSource":"Nota general de pedestales 2CED5","appearanceStatus":"criterio_visual","appearanceBasis":"Interpretación visual del material documental; el acabado, tono y parámetros PBR no son una especificación contractual.","note":"La apariencia gráfica no modifica ni confirma la especificación física del material."} | {"elementId":"found_0904_8a06daae7122ea","ifcGuid":"0Nfr51QGPTJOKko_7aAgLU","ifcClass":"IfcFooting","buildingId":"process_plant","buildingName":"Zona de separación de aire","sourceDocumentId":"LHD2609-JG00100-20260904","sourceRepresentationKind":"foundation"} | {"layerId":"foundations","layerName":"Cimentaciones","role":"Cimentación industrial","basis":"Clasificación por función del elemento; no modifica las especificaciones documentales."} | {"profileId":"concrete_ha30","name":"Hormigón HA-30","status":"criterio_visual","basis":"Interpretación visual del material documental; el acabado, tono y parámetros PBR no son una especificación contractual.","physicalMaterialUnchanged":true} | 0.4 | Hormigón HA-30 | Hormigón HA-30 | found_0904_8a06daae7122ea | Nota general de pedestales 2CED5 | documentado | concrete_ha30 | [0.658824,0.658824,0.623529] | 0.94 | Zona de separación de aire; BIM · Cimentaciones | 1.12689 | 1.12688 | 0.4 | 285.1 | 285.5 | SUP-C11 | [] | ["C11"] | ZD1 / DZ-1 | ["2CC77","2CD48","2CDAC","2CC78","2CC73","2CC74","2CD6D","2CEB1","2CE8C"] | SUP-C11/Cimentación de soporte de tuberías C11 · cuerpo de hormigón | foundation | Geometría de fabricante; implantación absoluta provisional |  | Cimentaciones de equipos y pedestales del fabricante · revisión recibida 04/09/2026 | 2CC77, 2CD48, 2CDAC, 2CC78, 2CC73, 2CC74, 2CD6D, 2CEB1, 2CE8C | -1 | -0.6 | 1 | Cotas relativas del dibujo. La equivalencia con un datum absoluto está pendiente. | Z del modelo = cota relativa + 1,10 m. Correspondencia provisional con 286,10 m; no es cota de obra confirmada. | Contornos y sección documentados por el fabricante | 1 | 1 | Material: Hormigón HA-30
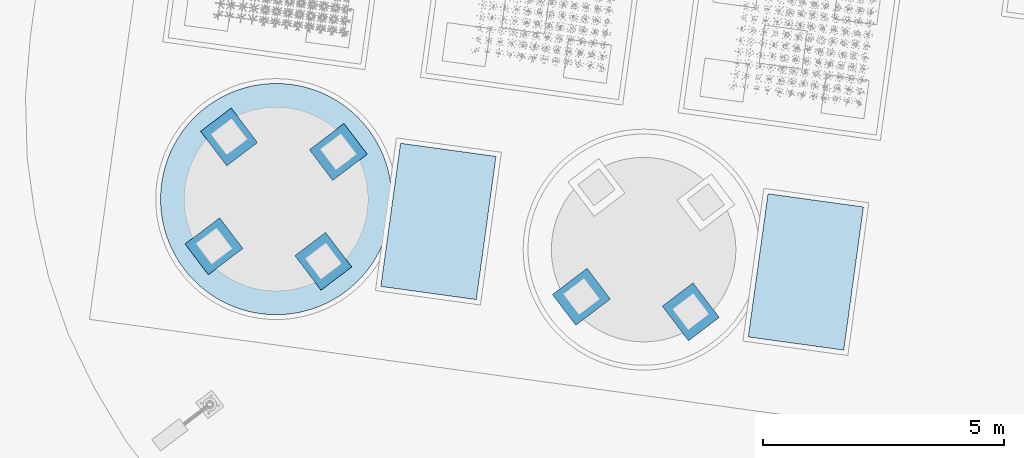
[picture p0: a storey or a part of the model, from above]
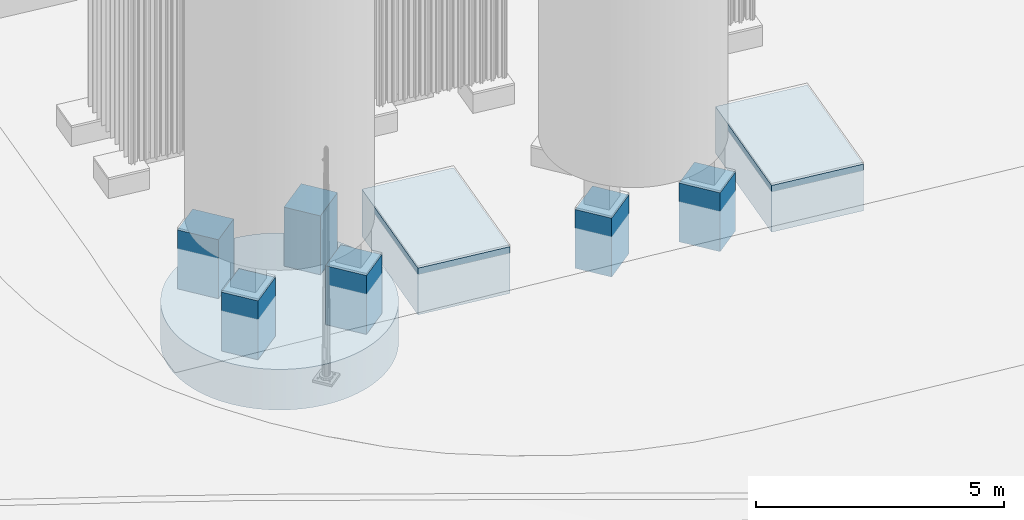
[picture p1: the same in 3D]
Properties of the parts of a building model (IFC4), part 80 of 134

# IfcFooting (214)
Name | In | Description = category = Categoria = Funcion | Document | ExtensionX (m) | ExtensionY (m) | ExtensionZ (m) | SuperficieDeLaMalla (m2) | VolumenGeometrico (m3) | buildingId | buildingName | material | dimensions | JH_InformacionBIM, source = DocumentoFuente | JH_InformacionBIM, status = EstadoDeInformacion | issues = IncidenciasPendientes | positioning = PosicionYEstado | geometryMetrics | materialAppearance | visualizationIdentity | classification | appearance | Volumen geométrico (m³) | JH_Trazabilidad, Material = name | Acabado de visualización = Acabado | Identificador | JH_EvidenciaDeMaterial, source | JH_EvidenciaDeMaterial, status | Perfil | ColorRGB | Rugosidad | Group | Extensión de la malla en X (m) | Extensión de la malla en Y (m) | Extensión de la malla en Z (m) = Espesor o altura real de sección (m) | Cota inferior de visualización (m) | Cota superior de visualización (m) | assemblyId = Conjunto de cimentación | equipmentIds | supportPositionIds | sectionRef = Sección de referencia | sourceCadHandles | stableElementKey | representationKind | geometryStatus | Equipos asociados | Documento de origen | Identificadores CAD de referencia | Cota inferior relativa (m) = Cota inferior relativa adoptada (m) | Cota superior relativa (m) = Cota superior relativa adoptada (m) | Área de planta (m²) | Referencia vertical | Implantación para visualización | Estado de la geometría | Extensión local X (m) | Extensión local Y (m) | Incidencias de origen
Cimentación de soporte de tuberías C11 · pedestal de hormigón | Parcela industrial Jinhong | Cimentación industrial | Cimentaciones de equipos y pedestales del fabricante · revisión recibida 04/09/2026 | 0.507098 | 0.507098 | 0.8 | 1.845 | 0.162 | process_plant | Zona de separación de aire | {"name":"Hormigón HA-30","status":"documentado","source":"Nota general de pedestales 2CED5"} | {"documented":[{"label":"Extensión local X","value":0.45,"unit":"m","source":"2CC77, 2CD48, 2CDAC, 2CC78, 2CC73, 2CC74, 2CD6D, 2CEB1, 2CE8C","status":"derivada del contorno CAD"},{"label":"Extensión local Y","value":0.45,"unit":"m","source":"2CC77, 2CD48, 2CDAC, 2CC78, 2CC73, 2CC74, 2CD6D, 2CEB1, 2CE8C","status":"derivada del contorno CAD"},{"label":"Cota inferior relativa adoptada","value":-0.6,"unit":"m","source":"ZD1 / DZ-1","status":"documentada"},{"label":"Cota superior relativa adoptada","value":0.2,"unit":"m","source":"ZD1 / DZ-1","status":"documentada / separación por material"}],"geometry":[{"label":"Extensión de la malla en X","value":0.5070980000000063,"unit":"m","source":"Geometría releída del IFC; datum absoluto de proceso provisional","status":"derivado"},{"label":"Extensión de la malla en Y","value":0.5070979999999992,"unit":"m","source":"Geometría releída del IFC; datum absoluto de proceso provisional","status":"derivado"},{"label":"Extensión de la malla en Z","value":0.8,"unit":"m","source":"Geometría releída del IFC; datum absoluto de proceso provisional","status":"derivado"},{"label":"Cota inferior de visualización","value":285.5,"unit":"m","source":"Geometría releída del IFC; datum absoluto de proceso provisional","status":"derivado"},{"label":"Cota superior de visualización","value":286.3,"unit":"m","source":"Geometría releída del IFC; datum absoluto de proceso provisional","status":"derivado"}]} | {"documentId":"LHD2609-JG00100-20260904","title":"Cimentaciones de equipos y pedestales del fabricante · revisión recibida 04/09/2026","date":"2026-09-04","sheet":"ZD1 / DZ-1","fileName":"LHD2609-JG00100_20260904.dwg","revisionCaveat":"Fecha de revisión tomada del nombre recibido; cajetines internos mantienen 02/07/2026 y algunos textos de plantilla.","sourceFileSha256":"b42eb027b7bc0b14c38d1d13514f4899b58a732aa8d0ba2ccf10fa2fc3192890"} | provisional | [] | {"Cota inferior relativa (m)":-0.6,"Cota superior relativa (m)":0.2,"Cero absoluto de visualización (m)":286.1,"Estado del cero absoluto":"Provisional","Criterio":"Las cotas relativas proceden del dibujo; la equivalencia absoluta no está confirmada."} | {"boundingBoxM":{"min":[44.335691,64.643715,0.5],"max":[44.842789,65.150813,1.3]},"extentsM":[0.507098,0.507098,0.8],"meshSurfaceM2":1.844999,"meshVolumeM3":0.162,"closedSolid":true,"basis":"Magnitudes de las mallas representadas, no cantidades certificadas de obra, compra o fabricación. Las partes pueden compartir superficies; no se suman como un despiece de materiales."} | {"profileId":"concrete_ha30","name":"Hormigón HA-30","materialName":"Hormigón HA-30","physicalMaterialStatus":"documentado","physicalMaterialSource":"Nota general de pedestales 2CED5","appearanceStatus":"criterio_visual","appearanceBasis":"Interpretación visual del material documental; el acabado, tono y parámetros PBR no son una especificación contractual.","note":"La apariencia gráfica no modifica ni confirma la especificación física del material."} | {"elementId":"found_0904_819fedb53af7a0","ifcGuid":"0_$0iKYHPKOgUegCcq79gb","ifcClass":"IfcFooting","buildingId":"process_plant","buildingName":"Zona de separación de aire","sourceDocumentId":"LHD2609-JG00100-20260904","sourceRepresentationKind":"foundation"} | {"layerId":"foundations","layerName":"Cimentaciones","role":"Cimentación industrial","basis":"Clasificación por función del elemento; no modifica las especificaciones documentales."} | {"profileId":"concrete_ha30","name":"Hormigón HA-30","status":"criterio_visual","basis":"Interpretación visual del material documental; el acabado, tono y parámetros PBR no son una especificación contractual.","physicalMaterialUnchanged":true} | 0.162 | Hormigón HA-30 | Hormigón HA-30 | found_0904_819fedb53af7a0 | Nota general de pedestales 2CED5 | documentado | concrete_ha30 | [0.658824,0.658824,0.623529] | 0.94 | Zona de separación de aire; BIM · Cimentaciones | 0.507098 | 0.507098 | 0.8 | 285.5 | 286.3 | SUP-C11 | [] | ["C11"] | ZD1 / DZ-1 | ["2CC77","2CD48","2CDAC","2CC78","2CC73","2CC74","2CD6D","2CEB1","2CE8C"] | SUP-C11/Cimentación de soporte de tuberías C11 · pedestal de hormigón | foundation | Geometría de fabricante; implantación absoluta provisional |  | Cimentaciones de equipos y pedestales del fabricante · revisión recibida 04/09/2026 | 2CC77, 2CD48, 2CDAC, 2CC78, 2CC73, 2CC74, 2CD6D, 2CEB1, 2CE8C | -0.6 | 0.2 | 0.2025 | Cotas relativas del dibujo. La equivalencia con un datum absoluto está pendiente. | Z del modelo = cota relativa + 1,10 m. Correspondencia provisional con 286,10 m; no es cota de obra confirmada. | Contornos y sección documentados por el fabricante | 0.45 | 0.45 | Material: Hormigón HA-30
Cimentación de soporte de tuberías C12 · cuerpo de hormigón | Parcela industrial Jinhong | Cimentación industrial | Cimentaciones de equipos y pedestales del fabricante · revisión recibida 04/09/2026 | 1.12689 | 1.12689 | 0.4 | 3.6 | 0.4 | process_plant | Zona de separación de aire | {"name":"Hormigón HA-30","status":"documentado","source":"Nota general de pedestales 2CED5"} | {"documented":[{"label":"Extensión local X","value":1.0,"unit":"m","source":"2CC7D, 2CD49, 2CDA8, 2CC7E, 2CC79, 2CC7A, 2CD6E, 2CEB2, 2CE8D","status":"derivada del contorno CAD"},{"label":"Extensión local Y","value":1.0,"unit":"m","source":"2CC7D, 2CD49, 2CDA8, 2CC7E, 2CC79, 2CC7A, 2CD6E, 2CEB2, 2CE8D","status":"derivada del contorno CAD"},{"label":"Cota inferior relativa adoptada","value":-1.0,"unit":"m","source":"ZD1 / DZ-1","status":"documentada"},{"label":"Cota superior relativa adoptada","value":-0.6,"unit":"m","source":"ZD1 / DZ-1","status":"documentada / separación por material"}],"geometry":[{"label":"Extensión de la malla en X","value":1.1268850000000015,"unit":"m","source":"Geometría releída del IFC; datum absoluto de proceso provisional","status":"derivado"},{"label":"Extensión de la malla en Y","value":1.1268850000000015,"unit":"m","source":"Geometría releída del IFC; datum absoluto de proceso provisional","status":"derivado"},{"label":"Extensión de la malla en Z","value":0.4,"unit":"m","source":"Geometría releída del IFC; datum absoluto de proceso provisional","status":"derivado"},{"label":"Cota inferior de visualización","value":285.1,"unit":"m","source":"Geometría releída del IFC; datum absoluto de proceso provisional","status":"derivado"},{"label":"Cota superior de visualización","value":285.5,"unit":"m","source":"Geometría releída del IFC; datum absoluto de proceso provisional","status":"derivado"}]} | {"documentId":"LHD2609-JG00100-20260904","title":"Cimentaciones de equipos y pedestales del fabricante · revisión recibida 04/09/2026","date":"2026-09-04","sheet":"ZD1 / DZ-1","fileName":"LHD2609-JG00100_20260904.dwg","revisionCaveat":"Fecha de revisión tomada del nombre recibido; cajetines internos mantienen 02/07/2026 y algunos textos de plantilla.","sourceFileSha256":"b42eb027b7bc0b14c38d1d13514f4899b58a732aa8d0ba2ccf10fa2fc3192890"} | provisional | [] | {"Cota inferior relativa (m)":-1.0,"Cota superior relativa (m)":-0.6,"Cero absoluto de visualización (m)":286.1,"Estado del cero absoluto":"Provisional","Criterio":"Las cotas relativas proceden del dibujo; la equivalencia absoluta no está confirmada."} | {"boundingBoxM":{"min":[45.165081,64.177187,0.1],"max":[46.291966,65.304072,0.5]},"extentsM":[1.126885,1.126885,0.4],"meshSurfaceM2":3.600001,"meshVolumeM3":0.4,"closedSolid":true,"basis":"Magnitudes de las mallas representadas, no cantidades certificadas de obra, compra o fabricación. Las partes pueden compartir superficies; no se suman como un despiece de materiales."} | {"profileId":"concrete_ha30","name":"Hormigón HA-30","materialName":"Hormigón HA-30","physicalMaterialStatus":"documentado","physicalMaterialSource":"Nota general de pedestales 2CED5","appearanceStatus":"criterio_visual","appearanceBasis":"Interpretación visual del material documental; el acabado, tono y parámetros PBR no son una especificación contractual.","note":"La apariencia gráfica no modifica ni confirma la especificación física del material."} | {"elementId":"found_0904_fbc6ebcace0d37","ifcGuid":"3ssot_eZbTE8JyyR7k2GVT","ifcClass":"IfcFooting","buildingId":"process_plant","buildingName":"Zona de separación de aire","sourceDocumentId":"LHD2609-JG00100-20260904","sourceRepresentationKind":"foundation"} | {"layerId":"foundations","layerName":"Cimentaciones","role":"Cimentación industrial","basis":"Clasificación por función del elemento; no modifica las especificaciones documentales."} | {"profileId":"concrete_ha30","name":"Hormigón HA-30","status":"criterio_visual","basis":"Interpretación visual del material documental; el acabado, tono y parámetros PBR no son una especificación contractual.","physicalMaterialUnchanged":true} | 0.4 | Hormigón HA-30 | Hormigón HA-30 | found_0904_fbc6ebcace0d37 | Nota general de pedestales 2CED5 | documentado | concrete_ha30 | [0.658824,0.658824,0.623529] | 0.94 | Zona de separación de aire; BIM · Cimentaciones | 1.12689 | 1.12689 | 0.4 | 285.1 | 285.5 | SUP-C12 | [] | ["C12"] | ZD1 / DZ-1 | ["2CC7D","2CD49","2CDA8","2CC7E","2CC79","2CC7A","2CD6E","2CEB2","2CE8D"] | SUP-C12/Cimentación de soporte de tuberías C12 · cuerpo de hormigón | foundation | Geometría de fabricante; implantación absoluta provisional |  | Cimentaciones de equipos y pedestales del fabricante · revisión recibida 04/09/2026 | 2CC7D, 2CD49, 2CDA8, 2CC7E, 2CC79, 2CC7A, 2CD6E, 2CEB2, 2CE8D | -1 | -0.6 | 1 | Cotas relativas del dibujo. La equivalencia con un datum absoluto está pendiente. | Z del modelo = cota relativa + 1,10 m. Correspondencia provisional con 286,10 m; no es cota de obra confirmada. | Contornos y sección documentados por el fabricante | 1 | 1 | Material: Hormigón HA-30
Cimentación de soporte de tuberías C12 · pedestal de hormigón | Parcela industrial Jinhong | Cimentación industrial | Cimentaciones de equipos y pedestales del fabricante · revisión recibida 04/09/2026 | 0.507098 | 0.507098 | 0.8 | 1.845 | 0.162 | process_plant | Zona de separación de aire | {"name":"Hormigón HA-30","status":"documentado","source":"Nota general de pedestales 2CED5"} | {"documented":[{"label":"Extensión local X","value":0.45,"unit":"m","source":"2CC7D, 2CD49, 2CDA8, 2CC7E, 2CC79, 2CC7A, 2CD6E, 2CEB2, 2CE8D","status":"derivada del contorno CAD"},{"label":"Extensión local Y","value":0.45,"unit":"m","source":"2CC7D, 2CD49, 2CDA8, 2CC7E, 2CC79, 2CC7A, 2CD6E, 2CEB2, 2CE8D","status":"derivada del contorno CAD"},{"label":"Cota inferior relativa adoptada","value":-0.6,"unit":"m","source":"ZD1 / DZ-1","status":"documentada"},{"label":"Cota superior relativa adoptada","value":0.2,"unit":"m","source":"ZD1 / DZ-1","status":"documentada / separación por material"}],"geometry":[{"label":"Extensión de la malla en X","value":0.5070979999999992,"unit":"m","source":"Geometría releída del IFC; datum absoluto de proceso provisional","status":"derivado"},{"label":"Extensión de la malla en Y","value":0.5070979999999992,"unit":"m","source":"Geometría releída del IFC; datum absoluto de proceso provisional","status":"derivado"},{"label":"Extensión de la malla en Z","value":0.8,"unit":"m","source":"Geometría releída del IFC; datum absoluto de proceso provisional","status":"derivado"},{"label":"Cota inferior de visualización","value":285.5,"unit":"m","source":"Geometría releída del IFC; datum absoluto de proceso provisional","status":"derivado"},{"label":"Cota superior de visualización","value":286.3,"unit":"m","source":"Geometría releída del IFC; datum absoluto de proceso provisional","status":"derivado"}]} | {"documentId":"LHD2609-JG00100-20260904","title":"Cimentaciones de equipos y pedestales del fabricante · revisión recibida 04/09/2026","date":"2026-09-04","sheet":"ZD1 / DZ-1","fileName":"LHD2609-JG00100_20260904.dwg","revisionCaveat":"Fecha de revisión tomada del nombre recibido; cajetines internos mantienen 02/07/2026 y algunos textos de plantilla.","sourceFileSha256":"b42eb027b7bc0b14c38d1d13514f4899b58a732aa8d0ba2ccf10fa2fc3192890"} | provisional | [] | {"Cota inferior relativa (m)":-0.6,"Cota superior relativa (m)":0.2,"Cero absoluto de visualización (m)":286.1,"Estado del cero absoluto":"Provisional","Criterio":"Las cotas relativas proceden del dibujo; la equivalencia absoluta no está confirmada."} | {"boundingBoxM":{"min":[45.474974,64.48708,0.5],"max":[45.982072,64.994178,1.3]},"extentsM":[0.507098,0.507098,0.8],"meshSurfaceM2":1.845,"meshVolumeM3":0.162,"closedSolid":true,"basis":"Magnitudes de las mallas representadas, no cantidades certificadas de obra, compra o fabricación. Las partes pueden compartir superficies; no se suman como un despiece de materiales."} | {"profileId":"concrete_ha30","name":"Hormigón HA-30","materialName":"Hormigón HA-30","physicalMaterialStatus":"documentado","physicalMaterialSource":"Nota general de pedestales 2CED5","appearanceStatus":"criterio_visual","appearanceBasis":"Interpretación visual del material documental; el acabado, tono y parámetros PBR no son una especificación contractual.","note":"La apariencia gráfica no modifica ni confirma la especificación física del material."} | {"elementId":"found_0904_6edb365a68c316","ifcGuid":"2xsXNuWuHG0QgGqyY4yzHE","ifcClass":"IfcFooting","buildingId":"process_plant","buildingName":"Zona de separación de aire","sourceDocumentId":"LHD2609-JG00100-20260904","sourceRepresentationKind":"foundation"} | {"layerId":"foundations","layerName":"Cimentaciones","role":"Cimentación industrial","basis":"Clasificación por función del elemento; no modifica las especificaciones documentales."} | {"profileId":"concrete_ha30","name":"Hormigón HA-30","status":"criterio_visual","basis":"Interpretación visual del material documental; el acabado, tono y parámetros PBR no son una especificación contractual.","physicalMaterialUnchanged":true} | 0.162 | Hormigón HA-30 | Hormigón HA-30 | found_0904_6edb365a68c316 | Nota general de pedestales 2CED5 | documentado | concrete_ha30 | [0.658824,0.658824,0.623529] | 0.94 | Zona de separación de aire; BIM · Cimentaciones | 0.507098 | 0.507098 | 0.8 | 285.5 | 286.3 | SUP-C12 | [] | ["C12"] | ZD1 / DZ-1 | ["2CC7D","2CD49","2CDA8","2CC7E","2CC79","2CC7A","2CD6E","2CEB2","2CE8D"] | SUP-C12/Cimentación de soporte de tuberías C12 · pedestal de hormigón | foundation | Geometría de fabricante; implantación absoluta provisional |  | Cimentaciones de equipos y pedestales del fabricante · revisión recibida 04/09/2026 | 2CC7D, 2CD49, 2CDA8, 2CC7E, 2CC79, 2CC7A, 2CD6E, 2CEB2, 2CE8D | -0.6 | 0.2 | 0.2025 | Cotas relativas del dibujo. La equivalencia con un datum absoluto está pendiente. | Z del modelo = cota relativa + 1,10 m. Correspondencia provisional con 286,10 m; no es cota de obra confirmada. | Contornos y sección documentados por el fabricante | 0.45 | 0.45 | Material: Hormigón HA-30
Cimentación de soporte de tuberías C13 · cuerpo de hormigón | Parcela industrial Jinhong | Cimentación industrial | Cimentaciones de equipos y pedestales del fabricante · revisión recibida 04/09/2026 | 1.12689 | 1.12688 | 0.4 | 3.6 | 0.4 | process_plant | Zona de separación de aire | {"name":"Hormigón HA-30","status":"documentado","source":"Nota general de pedestales 2CED5"} | {"documented":[{"label":"Extensión local X","value":1.0,"unit":"m","source":"2CC83, 2CD4A, 2CDA9, 2CC84, 2CC7F, 2CC80, 2CD6F, 2CEB3, 2CE8E","status":"derivada del contorno CAD"},{"label":"Extensión local Y","value":1.0,"unit":"m","source":"2CC83, 2CD4A, 2CDA9, 2CC84, 2CC7F, 2CC80, 2CD6F, 2CEB3, 2CE8E","status":"derivada del contorno CAD"},{"label":"Cota inferior relativa adoptada","value":-1.0,"unit":"m","source":"ZD1 / DZ-1","status":"documentada"},{"label":"Cota superior relativa adoptada","value":-0.6,"unit":"m","source":"ZD1 / DZ-1","status":"documentada / separación por material"}],"geometry":[{"label":"Extensión de la malla en X","value":1.1268850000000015,"unit":"m","source":"Geometría releída del IFC; datum absoluto de proceso provisional","status":"derivado"},{"label":"Extensión de la malla en Y","value":1.1268849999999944,"unit":"m","source":"Geometría releída del IFC; datum absoluto de proceso provisional","status":"derivado"},{"label":"Extensión de la malla en Z","value":0.4,"unit":"m","source":"Geometría releída del IFC; datum absoluto de proceso provisional","status":"derivado"},{"label":"Cota inferior de visualización","value":285.1,"unit":"m","source":"Geometría releída del IFC; datum absoluto de proceso provisional","status":"derivado"},{"label":"Cota superior de visualización","value":285.5,"unit":"m","source":"Geometría releída del IFC; datum absoluto de proceso provisional","status":"derivado"}]} | {"documentId":"LHD2609-JG00100-20260904","title":"Cimentaciones de equipos y pedestales del fabricante · revisión recibida 04/09/2026","date":"2026-09-04","sheet":"ZD1 / DZ-1","fileName":"LHD2609-JG00100_20260904.dwg","revisionCaveat":"Fecha de revisión tomada del nombre recibido; cajetines internos mantienen 02/07/2026 y algunos textos de plantilla.","sourceFileSha256":"b42eb027b7bc0b14c38d1d13514f4899b58a732aa8d0ba2ccf10fa2fc3192890"} | provisional | [] | {"Cota inferior relativa (m)":-1.0,"Cota superior relativa (m)":-0.6,"Cero absoluto de visualización (m)":286.1,"Estado del cero absoluto":"Provisional","Criterio":"Las cotas relativas proceden del dibujo; la equivalencia absoluta no está confirmada."} | {"boundingBoxM":{"min":[43.276676,58.885077,0.1],"max":[44.403561,60.011962,0.5]},"extentsM":[1.126885,1.126885,0.4],"meshSurfaceM2":3.600001,"meshVolumeM3":0.4,"closedSolid":true,"basis":"Magnitudes de las mallas representadas, no cantidades certificadas de obra, compra o fabricación. Las partes pueden compartir superficies; no se suman como un despiece de materiales."} | {"profileId":"concrete_ha30","name":"Hormigón HA-30","materialName":"Hormigón HA-30","physicalMaterialStatus":"documentado","physicalMaterialSource":"Nota general de pedestales 2CED5","appearanceStatus":"criterio_visual","appearanceBasis":"Interpretación visual del material documental; el acabado, tono y parámetros PBR no son una especificación contractual.","note":"La apariencia gráfica no modifica ni confirma la especificación física del material."} | {"elementId":"found_0904_95494f4f001af8","ifcGuid":"1uAYcOsX5QoP0lWnsM2n$v","ifcClass":"IfcFooting","buildingId":"process_plant","buildingName":"Zona de separación de aire","sourceDocumentId":"LHD2609-JG00100-20260904","sourceRepresentationKind":"foundation"} | {"layerId":"foundations","layerName":"Cimentaciones","role":"Cimentación industrial","basis":"Clasificación por función del elemento; no modifica las especificaciones documentales."} | {"profileId":"concrete_ha30","name":"Hormigón HA-30","status":"criterio_visual","basis":"Interpretación visual del material documental; el acabado, tono y parámetros PBR no son una especificación contractual.","physicalMaterialUnchanged":true} | 0.4 | Hormigón HA-30 | Hormigón HA-30 | found_0904_95494f4f001af8 | Nota general de pedestales 2CED5 | documentado | concrete_ha30 | [0.658824,0.658824,0.623529] | 0.94 | Zona de separación de aire; BIM · Cimentaciones | 1.12689 | 1.12688 | 0.4 | 285.1 | 285.5 | SUP-C13 | [] | ["C13"] | ZD1 / DZ-1 | ["2CC83","2CD4A","2CDA9","2CC84","2CC7F","2CC80","2CD6F","2CEB3","2CE8E"] | SUP-C13/Cimentación de soporte de tuberías C13 · cuerpo de hormigón | foundation | Geometría de fabricante; implantación absoluta provisional |  | Cimentaciones de equipos y pedestales del fabricante · revisión recibida 04/09/2026 | 2CC83, 2CD4A, 2CDA9, 2CC84, 2CC7F, 2CC80, 2CD6F, 2CEB3, 2CE8E | -1 | -0.6 | 1 | Cotas relativas del dibujo. La equivalencia con un datum absoluto está pendiente. | Z del modelo = cota relativa + 1,10 m. Correspondencia provisional con 286,10 m; no es cota de obra confirmada. | Contornos y sección documentados por el fabricante | 1 | 1 | Material: Hormigón HA-30
Cimentación de soporte de tuberías C13 · pedestal de hormigón | Parcela industrial Jinhong | Cimentación industrial | Cimentaciones de equipos y pedestales del fabricante · revisión recibida 04/09/2026 | 0.507098 | 0.507098 | 0.8 | 1.845 | 0.162 | process_plant | Zona de separación de aire | {"name":"Hormigón HA-30","status":"documentado","source":"Nota general de pedestales 2CED5"} | {"documented":[{"label":"Extensión local X","value":0.45,"unit":"m","source":"2CC83, 2CD4A, 2CDA9, 2CC84, 2CC7F, 2CC80, 2CD6F, 2CEB3, 2CE8E","status":"derivada del contorno CAD"},{"label":"Extensión local Y","value":0.45,"unit":"m","source":"2CC83, 2CD4A, 2CDA9, 2CC84, 2CC7F, 2CC80, 2CD6F, 2CEB3, 2CE8E","status":"derivada del contorno CAD"},{"label":"Cota inferior relativa adoptada","value":-0.6,"unit":"m","source":"ZD1 / DZ-1","status":"documentada"},{"label":"Cota superior relativa adoptada","value":0.2,"unit":"m","source":"ZD1 / DZ-1","status":"documentada / separación por material"}],"geometry":[{"label":"Extensión de la malla en X","value":0.5070979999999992,"unit":"m","source":"Geometría releída del IFC; datum absoluto de proceso provisional","status":"derivado"},{"label":"Extensión de la malla en Y","value":0.5070979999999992,"unit":"m","source":"Geometría releída del IFC; datum absoluto de proceso provisional","status":"derivado"},{"label":"Extensión de la malla en Z","value":0.8,"unit":"m","source":"Geometría releída del IFC; datum absoluto de proceso provisional","status":"derivado"},{"label":"Cota inferior de visualización","value":285.5,"unit":"m","source":"Geometría releída del IFC; datum absoluto de proceso provisional","status":"derivado"},{"label":"Cota superior de visualización","value":286.3,"unit":"m","source":"Geometría releída del IFC; datum absoluto de proceso provisional","status":"derivado"}]} | {"documentId":"LHD2609-JG00100-20260904","title":"Cimentaciones de equipos y pedestales del fabricante · revisión recibida 04/09/2026","date":"2026-09-04","sheet":"ZD1 / DZ-1","fileName":"LHD2609-JG00100_20260904.dwg","revisionCaveat":"Fecha de revisión tomada del nombre recibido; cajetines internos mantienen 02/07/2026 y algunos textos de plantilla.","sourceFileSha256":"b42eb027b7bc0b14c38d1d13514f4899b58a732aa8d0ba2ccf10fa2fc3192890"} | provisional | [] | {"Cota inferior relativa (m)":-0.6,"Cota superior relativa (m)":0.2,"Cero absoluto de visualización (m)":286.1,"Estado del cero absoluto":"Provisional","Criterio":"Las cotas relativas proceden del dibujo; la equivalencia absoluta no está confirmada."} | {"boundingBoxM":{"min":[43.58657,59.19497,0.5],"max":[44.093668,59.702068,1.3]},"extentsM":[0.507098,0.507098,0.8],"meshSurfaceM2":1.844999,"meshVolumeM3":0.162,"closedSolid":true,"basis":"Magnitudes de las mallas representadas, no cantidades certificadas de obra, compra o fabricación. Las partes pueden compartir superficies; no se suman como un despiece de materiales."} | {"profileId":"concrete_ha30","name":"Hormigón HA-30","materialName":"Hormigón HA-30","physicalMaterialStatus":"documentado","physicalMaterialSource":"Nota general de pedestales 2CED5","appearanceStatus":"criterio_visual","appearanceBasis":"Interpretación visual del material documental; el acabado, tono y parámetros PBR no son una especificación contractual.","note":"La apariencia gráfica no modifica ni confirma la especificación física del material."} | {"elementId":"found_0904_0de613fc2cda41","ifcGuid":"0$9cfcuqPOVvtxlMo1mWRU","ifcClass":"IfcFooting","buildingId":"process_plant","buildingName":"Zona de separación de aire","sourceDocumentId":"LHD2609-JG00100-20260904","sourceRepresentationKind":"foundation"} | {"layerId":"foundations","layerName":"Cimentaciones","role":"Cimentación industrial","basis":"Clasificación por función del elemento; no modifica las especificaciones documentales."} | {"profileId":"concrete_ha30","name":"Hormigón HA-30","status":"criterio_visual","basis":"Interpretación visual del material documental; el acabado, tono y parámetros PBR no son una especificación contractual.","physicalMaterialUnchanged":true} | 0.162 | Hormigón HA-30 | Hormigón HA-30 | found_0904_0de613fc2cda41 | Nota general de pedestales 2CED5 | documentado | concrete_ha30 | [0.658824,0.658824,0.623529] | 0.94 | Zona de separación de aire; BIM · Cimentaciones | 0.507098 | 0.507098 | 0.8 | 285.5 | 286.3 | SUP-C13 | [] | ["C13"] | ZD1 / DZ-1 | ["2CC83","2CD4A","2CDA9","2CC84","2CC7F","2CC80","2CD6F","2CEB3","2CE8E"] | SUP-C13/Cimentación de soporte de tuberías C13 · pedestal de hormigón | foundation | Geometría de fabricante; implantación absoluta provisional |  | Cimentaciones de equipos y pedestales del fabricante · revisión recibida 04/09/2026 | 2CC83, 2CD4A, 2CDA9, 2CC84, 2CC7F, 2CC80, 2CD6F, 2CEB3, 2CE8E | -0.6 | 0.2 | 0.2025 | Cotas relativas del dibujo. La equivalencia con un datum absoluto está pendiente. | Z del modelo = cota relativa + 1,10 m. Correspondencia provisional con 286,10 m; no es cota de obra confirmada. | Contornos y sección documentados por el fabricante | 0.45 | 0.45 | Material: Hormigón HA-30
Cimentación de soporte de tuberías C14 · cuerpo de hormigón | Parcela industrial Jinhong | Cimentación industrial | Cimentaciones de equipos y pedestales del fabricante · revisión recibida 04/09/2026 | 1.12689 | 1.12688 | 0.4 | 3.6 | 0.4 | process_plant | Zona de separación de aire | {"name":"Hormigón HA-30","status":"documentado","source":"Nota general de pedestales 2CED5"} | {"documented":[{"label":"Extensión local X","value":1.0,"unit":"m","source":"2CC89, 2CD4B, 2CDA7, 2CC8A, 2CC85, 2CC86, 2CD70, 2CEB4, 2CE8F","status":"derivada del contorno CAD"},{"label":"Extensión local Y","value":1.0,"unit":"m","source":"2CC89, 2CD4B, 2CDA7, 2CC8A, 2CC85, 2CC86, 2CD70, 2CEB4, 2CE8F","status":"derivada del contorno CAD"},{"label":"Cota inferior relativa adoptada","value":-1.0,"unit":"m","source":"ZD1 / DZ-1","status":"documentada"},{"label":"Cota superior relativa adoptada","value":-0.6,"unit":"m","source":"ZD1 / DZ-1","status":"documentada / separación por material"}],"geometry":[{"label":"Extensión de la malla en X","value":1.1268850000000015,"unit":"m","source":"Geometría releída del IFC; datum absoluto de proceso provisional","status":"derivado"},{"label":"Extensión de la malla en Y","value":1.126884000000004,"unit":"m","source":"Geometría releída del IFC; datum absoluto de proceso provisional","status":"derivado"},{"label":"Extensión de la malla en Z","value":0.4,"unit":"m","source":"Geometría releída del IFC; datum absoluto de proceso provisional","status":"derivado"},{"label":"Cota inferior de visualización","value":285.1,"unit":"m","source":"Geometría releída del IFC; datum absoluto de proceso provisional","status":"derivado"},{"label":"Cota superior de visualización","value":285.5,"unit":"m","source":"Geometría releída del IFC; datum absoluto de proceso provisional","status":"derivado"}]} | {"documentId":"LHD2609-JG00100-20260904","title":"Cimentaciones de equipos y pedestales del fabricante · revisión recibida 04/09/2026","date":"2026-09-04","sheet":"ZD1 / DZ-1","fileName":"LHD2609-JG00100_20260904.dwg","revisionCaveat":"Fecha de revisión tomada del nombre recibido; cajetines internos mantienen 02/07/2026 y algunos textos de plantilla.","sourceFileSha256":"b42eb027b7bc0b14c38d1d13514f4899b58a732aa8d0ba2ccf10fa2fc3192890"} | provisional | [] | {"Cota inferior relativa (m)":-1.0,"Cota superior relativa (m)":-0.6,"Cero absoluto de visualización (m)":286.1,"Estado del cero absoluto":"Provisional","Criterio":"Las cotas relativas proceden del dibujo; la equivalencia absoluta no está confirmada."} | {"boundingBoxM":{"min":[44.415959,58.728443,0.1],"max":[45.542844,59.855327,0.5]},"extentsM":[1.126885,1.126884,0.4],"meshSurfaceM2":3.599999,"meshVolumeM3":0.4,"closedSolid":true,"basis":"Magnitudes de las mallas representadas, no cantidades certificadas de obra, compra o fabricación. Las partes pueden compartir superficies; no se suman como un despiece de materiales."} | {"profileId":"concrete_ha30","name":"Hormigón HA-30","materialName":"Hormigón HA-30","physicalMaterialStatus":"documentado","physicalMaterialSource":"Nota general de pedestales 2CED5","appearanceStatus":"criterio_visual","appearanceBasis":"Interpretación visual del material documental; el acabado, tono y parámetros PBR no son una especificación contractual.","note":"La apariencia gráfica no modifica ni confirma la especificación física del material."} | {"elementId":"found_0904_f9e84f287233c1","ifcGuid":"0AUpFi5_vNlgiEN6vNcORM","ifcClass":"IfcFooting","buildingId":"process_plant","buildingName":"Zona de separación de aire","sourceDocumentId":"LHD2609-JG00100-20260904","sourceRepresentationKind":"foundation"} | {"layerId":"foundations","layerName":"Cimentaciones","role":"Cimentación industrial","basis":"Clasificación por función del elemento; no modifica las especificaciones documentales."} | {"profileId":"concrete_ha30","name":"Hormigón HA-30","status":"criterio_visual","basis":"Interpretación visual del material documental; el acabado, tono y parámetros PBR no son una especificación contractual.","physicalMaterialUnchanged":true} | 0.4 | Hormigón HA-30 | Hormigón HA-30 | found_0904_f9e84f287233c1 | Nota general de pedestales 2CED5 | documentado | concrete_ha30 | [0.658824,0.658824,0.623529] | 0.94 | Zona de separación de aire; BIM · Cimentaciones | 1.12689 | 1.12688 | 0.4 | 285.1 | 285.5 | SUP-C14 | [] | ["C14"] | ZD1 / DZ-1 | ["2CC89","2CD4B","2CDA7","2CC8A","2CC85","2CC86","2CD70","2CEB4","2CE8F"] | SUP-C14/Cimentación de soporte de tuberías C14 · cuerpo de hormigón | foundation | Geometría de fabricante; implantación absoluta provisional |  | Cimentaciones de equipos y pedestales del fabricante · revisión recibida 04/09/2026 | 2CC89, 2CD4B, 2CDA7, 2CC8A, 2CC85, 2CC86, 2CD70, 2CEB4, 2CE8F | -1 | -0.6 | 1 | Cotas relativas del dibujo. La equivalencia con un datum absoluto está pendiente. | Z del modelo = cota relativa + 1,10 m. Correspondencia provisional con 286,10 m; no es cota de obra confirmada. | Contornos y sección documentados por el fabricante | 1 | 1 | Material: Hormigón HA-30
Cimentación de soporte de tuberías C14 · pedestal de hormigón | Parcela industrial Jinhong | Cimentación industrial | Cimentaciones de equipos y pedestales del fabricante · revisión recibida 04/09/2026 | 0.507098 | 0.507098 | 0.8 | 1.845 | 0.162 | process_plant | Zona de separación de aire | {"name":"Hormigón HA-30","status":"documentado","source":"Nota general de pedestales 2CED5"} | {"documented":[{"label":"Extensión local X","value":0.45,"unit":"m","source":"2CC89, 2CD4B, 2CDA7, 2CC8A, 2CC85, 2CC86, 2CD70, 2CEB4, 2CE8F","status":"derivada del contorno CAD"},{"label":"Extensión local Y","value":0.45,"unit":"m","source":"2CC89, 2CD4B, 2CDA7, 2CC8A, 2CC85, 2CC86, 2CD70, 2CEB4, 2CE8F","status":"derivada del contorno CAD"},{"label":"Cota inferior relativa adoptada","value":-0.6,"unit":"m","source":"ZD1 / DZ-1","status":"documentada"},{"label":"Cota superior relativa adoptada","value":0.2,"unit":"m","source":"ZD1 / DZ-1","status":"documentada / separación por material"}],"geometry":[{"label":"Extensión de la malla en X","value":0.5070979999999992,"unit":"m","source":"Geometría releída del IFC; datum absoluto de proceso provisional","status":"derivado"},{"label":"Extensión de la malla en Y","value":0.5070979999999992,"unit":"m","source":"Geometría releída del IFC; datum absoluto de proceso provisional","status":"derivado"},{"label":"Extensión de la malla en Z","value":0.8,"unit":"m","source":"Geometría releída del IFC; datum absoluto de proceso provisional","status":"derivado"},{"label":"Cota inferior de visualización","value":285.5,"unit":"m","source":"Geometría releída del IFC; datum absoluto de proceso provisional","status":"derivado"},{"label":"Cota superior de visualización","value":286.3,"unit":"m","source":"Geometría releída del IFC; datum absoluto de proceso provisional","status":"derivado"}]} | {"documentId":"LHD2609-JG00100-20260904","title":"Cimentaciones de equipos y pedestales del fabricante · revisión recibida 04/09/2026","date":"2026-09-04","sheet":"ZD1 / DZ-1","fileName":"LHD2609-JG00100_20260904.dwg","revisionCaveat":"Fecha de revisión tomada del nombre recibido; cajetines internos mantienen 02/07/2026 y algunos textos de plantilla.","sourceFileSha256":"b42eb027b7bc0b14c38d1d13514f4899b58a732aa8d0ba2ccf10fa2fc3192890"} | provisional | [] | {"Cota inferior relativa (m)":-0.6,"Cota superior relativa (m)":0.2,"Cero absoluto de visualización (m)":286.1,"Estado del cero absoluto":"Provisional","Criterio":"Las cotas relativas proceden del dibujo; la equivalencia absoluta no está confirmada."} | {"boundingBoxM":{"min":[44.725853,59.038336,0.5],"max":[45.232951,59.545434,1.3]},"extentsM":[0.507098,0.507098,0.8],"meshSurfaceM2":1.844999,"meshVolumeM3":0.162,"closedSolid":true,"basis":"Magnitudes de las mallas representadas, no cantidades certificadas de obra, compra o fabricación. Las partes pueden compartir superficies; no se suman como un despiece de materiales."} | {"profileId":"concrete_ha30","name":"Hormigón HA-30","materialName":"Hormigón HA-30","physicalMaterialStatus":"documentado","physicalMaterialSource":"Nota general de pedestales 2CED5","appearanceStatus":"criterio_visual","appearanceBasis":"Interpretación visual del material documental; el acabado, tono y parámetros PBR no son una especificación contractual.","note":"La apariencia gráfica no modifica ni confirma la especificación física del material."} | {"elementId":"found_0904_cd3f45d251d463","ifcGuid":"3OIN5vREjMnveHKMZjGUbV","ifcClass":"IfcFooting","buildingId":"process_plant","buildingName":"Zona de separación de aire","sourceDocumentId":"LHD2609-JG00100-20260904","sourceRepresentationKind":"foundation"} | {"layerId":"foundations","layerName":"Cimentaciones","role":"Cimentación industrial","basis":"Clasificación por función del elemento; no modifica las especificaciones documentales."} | {"profileId":"concrete_ha30","name":"Hormigón HA-30","status":"criterio_visual","basis":"Interpretación visual del material documental; el acabado, tono y parámetros PBR no son una especificación contractual.","physicalMaterialUnchanged":true} | 0.162 | Hormigón HA-30 | Hormigón HA-30 | found_0904_cd3f45d251d463 | Nota general de pedestales 2CED5 | documentado | concrete_ha30 | [0.658824,0.658824,0.623529] | 0.94 | Zona de separación de aire; BIM · Cimentaciones | 0.507098 | 0.507098 | 0.8 | 285.5 | 286.3 | SUP-C14 | [] | ["C14"] | ZD1 / DZ-1 | ["2CC89","2CD4B","2CDA7","2CC8A","2CC85","2CC86","2CD70","2CEB4","2CE8F"] | SUP-C14/Cimentación de soporte de tuberías C14 · pedestal de hormigón | foundation | Geometría de fabricante; implantación absoluta provisional |  | Cimentaciones de equipos y pedestales del fabricante · revisión recibida 04/09/2026 | 2CC89, 2CD4B, 2CDA7, 2CC8A, 2CC85, 2CC86, 2CD70, 2CEB4, 2CE8F | -0.6 | 0.2 | 0.2025 | Cotas relativas del dibujo. La equivalencia con un datum absoluto está pendiente. | Z del modelo = cota relativa + 1,10 m. Correspondencia provisional con 286,10 m; no es cota de obra confirmada. | Contornos y sección documentados por el fabricante | 0.45 | 0.45 | Material: Hormigón HA-30
Cimentación de marquesina C15 · cuerpo de hormigón | Parcela industrial Jinhong | Cimentación industrial | Cimentaciones de equipos y pedestales del fabricante · revisión recibida 04/09/2026 | 1.23957 | 1.23957 | 0.5 | 4.62 | 0.605 | process_plant | Zona de separación de aire | {"name":"Hormigón HA-30","status":"documentado","source":"Nota general de pedestales 2CED5"} | {"documented":[{"label":"Extensión local X","value":1.1,"unit":"m","source":"2CC9F, 2CD4C, 2CCBE, 2CD8C, 2CCB0, 2CCB1, 2CD71, 2CEF2, 2CEF1","status":"derivada del contorno CAD"},{"label":"Extensión local Y","value":1.1,"unit":"m","source":"2CC9F, 2CD4C, 2CCBE, 2CD8C, 2CCB0, 2CCB1, 2CD71, 2CEF2, 2CEF1","status":"derivada del contorno CAD"},{"label":"Cota inferior relativa adoptada","value":-1.5,"unit":"m","source":"JC1 / DZ","status":"documentada"},{"label":"Cota superior relativa adoptada","value":-1,"unit":"m","source":"JC1 / DZ","status":"documentada / separación por material"}],"geometry":[{"label":"Extensión de la malla en X","value":1.2395740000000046,"unit":"m","source":"Geometría releída del IFC; datum absoluto de proceso provisional","status":"derivado"},{"label":"Extensión de la malla en Y","value":1.239573,"unit":"m","source":"Geometría releída del IFC; datum absoluto de proceso provisional","status":"derivado"},{"label":"Extensión de la malla en Z","value":0.5,"unit":"m","source":"Geometría releída del IFC; datum absoluto de proceso provisional","status":"derivado"},{"label":"Cota inferior de visualización","value":284.6,"unit":"m","source":"Geometría releída del IFC; datum absoluto de proceso provisional","status":"derivado"},{"label":"Cota superior de visualización","value":285.1,"unit":"m","source":"Geometría releída del IFC; datum absoluto de proceso provisional","status":"derivado"}]} | {"documentId":"LHD2609-JG00100-20260904","title":"Cimentaciones de equipos y pedestales del fabricante · revisión recibida 04/09/2026","date":"2026-09-04","sheet":"JC1 / DZ","fileName":"LHD2609-JG00100_20260904.dwg","revisionCaveat":"Fecha de revisión tomada del nombre recibido; cajetines internos mantienen 02/07/2026 y algunos textos de plantilla.","sourceFileSha256":"b42eb027b7bc0b14c38d1d13514f4899b58a732aa8d0ba2ccf10fa2fc3192890"} | provisional | [] | {"Cota inferior relativa (m)":-1.5,"Cota superior relativa (m)":-1,"Cero absoluto de visualización (m)":286.1,"Estado del cero absoluto":"Provisional","Criterio":"Las cotas relativas proceden del dibujo; la equivalencia absoluta no está confirmada."} | {"boundingBoxM":{"min":[36.398284,57.84879,-0.4],"max":[37.637858,59.088363,0.1]},"extentsM":[1.239574,1.239573,0.5],"meshSurfaceM2":4.619999,"meshVolumeM3":0.605,"closedSolid":true,"basis":"Magnitudes de las mallas representadas, no cantidades certificadas de obra, compra o fabricación. Las partes pueden compartir superficies; no se suman como un despiece de materiales."} | {"profileId":"concrete_ha30","name":"Hormigón HA-30","materialName":"Hormigón HA-30","physicalMaterialStatus":"documentado","physicalMaterialSource":"Nota general de pedestales 2CED5","appearanceStatus":"criterio_visual","appearanceBasis":"Interpretación visual del material documental; el acabado, tono y parámetros PBR no son una especificación contractual.","note":"La apariencia gráfica no modifica ni confirma la especificación física del material."} | {"elementId":"found_0904_ba518036427c5f","ifcGuid":"3LGWRbpzjRGPEUS5JzomjH","ifcClass":"IfcFooting","buildingId":"process_plant","buildingName":"Zona de separación de aire","sourceDocumentId":"LHD2609-JG00100-20260904","sourceRepresentationKind":"foundation"} | {"layerId":"foundations","layerName":"Cimentaciones","role":"Cimentación industrial","basis":"Clasificación por función del elemento; no modifica las especificaciones documentales."} | {"profileId":"concrete_ha30","name":"Hormigón HA-30","status":"criterio_visual","basis":"Interpretación visual del material documental; el acabado, tono y parámetros PBR no son una especificación contractual.","physicalMaterialUnchanged":true} | 0.605 | Hormigón HA-30 | Hormigón HA-30 | found_0904_ba518036427c5f | Nota general de pedestales 2CED5 | documentado | concrete_ha30 | [0.658824,0.658824,0.623529] | 0.94 | Zona de separación de aire; BIM · Cimentaciones | 1.23957 | 1.23957 | 0.5 | 284.6 | 285.1 | SUP-C15 | [] | ["C15"] | JC1 / DZ | ["2CC9F","2CD4C","2CCBE","2CD8C","2CCB0","2CCB1","2CD71","2CEF2","2CEF1"] | SUP-C15/Cimentación de marquesina C15 · cuerpo de hormigón | foundation | Geometría de fabricante; implantación absoluta provisional |  | Cimentaciones de equipos y pedestales del fabricante · revisión recibida 04/09/2026 | 2CC9F, 2CD4C, 2CCBE, 2CD8C, 2CCB0, 2CCB1, 2CD71, 2CEF2, 2CEF1 | -1.5 | -1 | 1.21 | Cotas relativas del dibujo. La equivalencia con un datum absoluto está pendiente. | Z del modelo = cota relativa + 1,10 m. Correspondencia provisional con 286,10 m; no es cota de obra confirmada. | Contornos y sección documentados por el fabricante | 1.1 | 1.1 | Material: Hormigón HA-30
Cimentación de marquesina C15 · pedestal de hormigón | Parcela industrial Jinhong | Cimentación industrial | Cimentaciones de equipos y pedestales del fabricante · revisión recibida 04/09/2026 | 0.563442 | 0.563442 | 1.2 | 2.9 | 0.3 | process_plant | Zona de separación de aire | {"name":"Hormigón HA-30","status":"documentado","source":"Nota general de pedestales 2CED5"} | {"documented":[{"label":"Extensión local X","value":0.5,"unit":"m","source":"2CC9F, 2CD4C, 2CCBE, 2CD8C, 2CCB0, 2CCB1, 2CD71, 2CEF2, 2CEF1","status":"derivada del contorno CAD"},{"label":"Extensión local Y","value":0.5,"unit":"m","source":"2CC9F, 2CD4C, 2CCBE, 2CD8C, 2CCB0, 2CCB1, 2CD71, 2CEF2, 2CEF1","status":"derivada del contorno CAD"},{"label":"Cota inferior relativa adoptada","value":-1,"unit":"m","source":"JC1 / DZ","status":"documentada"},{"label":"Cota superior relativa adoptada","value":0.2,"unit":"m","source":"JC1 / DZ","status":"documentada / separación por material"}],"geometry":[{"label":"Extensión de la malla en X","value":0.5634419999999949,"unit":"m","source":"Geometría releída del IFC; datum absoluto de proceso provisional","status":"derivado"},{"label":"Extensión de la malla en Y","value":0.563442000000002,"unit":"m","source":"Geometría releída del IFC; datum absoluto de proceso provisional","status":"derivado"},{"label":"Extensión de la malla en Z","value":1.2,"unit":"m","source":"Geometría releída del IFC; datum absoluto de proceso provisional","status":"derivado"},{"label":"Cota inferior de visualización","value":285.1,"unit":"m","source":"Geometría releída del IFC; datum absoluto de proceso provisional","status":"derivado"},{"label":"Cota superior de visualización","value":286.3,"unit":"m","source":"Geometría releída del IFC; datum absoluto de proceso provisional","status":"derivado"}]} | {"documentId":"LHD2609-JG00100-20260904","title":"Cimentaciones de equipos y pedestales del fabricante · revisión recibida 04/09/2026","date":"2026-09-04","sheet":"JC1 / DZ","fileName":"LHD2609-JG00100_20260904.dwg","revisionCaveat":"Fecha de revisión tomada del nombre recibido; cajetines internos mantienen 02/07/2026 y algunos textos de plantilla.","sourceFileSha256":"b42eb027b7bc0b14c38d1d13514f4899b58a732aa8d0ba2ccf10fa2fc3192890"} | provisional | [] | {"Cota inferior relativa (m)":-1,"Cota superior relativa (m)":0.2,"Cero absoluto de visualización (m)":286.1,"Estado del cero absoluto":"Provisional","Criterio":"Las cotas relativas proceden del dibujo; la equivalencia absoluta no está confirmada."} | {"boundingBoxM":{"min":[36.73635,58.186856,0.1],"max":[37.299792,58.750298,1.3]},"extentsM":[0.563442,0.563442,1.2],"meshSurfaceM2":2.899997,"meshVolumeM3":0.3,"closedSolid":true,"basis":"Magnitudes de las mallas representadas, no cantidades certificadas de obra, compra o fabricación. Las partes pueden compartir superficies; no se suman como un despiece de materiales."} | {"profileId":"concrete_ha30","name":"Hormigón HA-30","materialName":"Hormigón HA-30","physicalMaterialStatus":"documentado","physicalMaterialSource":"Nota general de pedestales 2CED5","appearanceStatus":"criterio_visual","appearanceBasis":"Interpretación visual del material documental; el acabado, tono y parámetros PBR no son una especificación contractual.","note":"La apariencia gráfica no modifica ni confirma la especificación física del material."} | {"elementId":"found_0904_164fb29052abc5","ifcGuid":"3sLmNk98HRSuYceOP7uiGS","ifcClass":"IfcFooting","buildingId":"process_plant","buildingName":"Zona de separación de aire","sourceDocumentId":"LHD2609-JG00100-20260904","sourceRepresentationKind":"foundation"} | {"layerId":"foundations","layerName":"Cimentaciones","role":"Cimentación industrial","basis":"Clasificación por función del elemento; no modifica las especificaciones documentales."} | {"profileId":"concrete_ha30","name":"Hormigón HA-30","status":"criterio_visual","basis":"Interpretación visual del material documental; el acabado, tono y parámetros PBR no son una especificación contractual.","physicalMaterialUnchanged":true} | 0.3 | Hormigón HA-30 | Hormigón HA-30 | found_0904_164fb29052abc5 | Nota general de pedestales 2CED5 | documentado | concrete_ha30 | [0.658824,0.658824,0.623529] | 0.94 | Zona de separación de aire; BIM · Cimentaciones | 0.563442 | 0.563442 | 1.2 | 285.1 | 286.3 | SUP-C15 | [] | ["C15"] | JC1 / DZ | ["2CC9F","2CD4C","2CCBE","2CD8C","2CCB0","2CCB1","2CD71","2CEF2","2CEF1"] | SUP-C15/Cimentación de marquesina C15 · pedestal de hormigón | foundation | Geometría de fabricante; implantación absoluta provisional |  | Cimentaciones de equipos y pedestales del fabricante · revisión recibida 04/09/2026 | 2CC9F, 2CD4C, 2CCBE, 2CD8C, 2CCB0, 2CCB1, 2CD71, 2CEF2, 2CEF1 | -1 | 0.2 | 0.25 | Cotas relativas del dibujo. La equivalencia con un datum absoluto está pendiente. | Z del modelo = cota relativa + 1,10 m. Correspondencia provisional con 286,10 m; no es cota de obra confirmada. | Contornos y sección documentados por el fabricante | 0.5 | 0.5 | Material: Hormigón HA-30
Cimentación de marquesina C16 · cuerpo de hormigón | Parcela industrial Jinhong | Cimentación industrial | Cimentaciones de equipos y pedestales del fabricante · revisión recibida 04/09/2026 | 1.23957 | 1.23957 | 0.5 | 4.62 | 0.605 | process_plant | Zona de separación de aire | {"name":"Hormigón HA-30","status":"documentado","source":"Nota general de pedestales 2CED5"} | {"documented":[{"label":"Extensión local X","value":1.1,"unit":"m","source":"2CCA0, 2CD4D, 2CCBF, 2CD8D, 2CCAE, 2CCAF, 2CD72, 2CEF4, 2CEF3","status":"derivada del contorno CAD"},{"label":"Extensión local Y","value":1.1,"unit":"m","source":"2CCA0, 2CD4D, 2CCBF, 2CD8D, 2CCAE, 2CCAF, 2CD72, 2CEF4, 2CEF3","status":"derivada del contorno CAD"},{"label":"Cota inferior relativa adoptada","value":-1.5,"unit":"m","source":"JC1 / DZ","status":"documentada"},{"label":"Cota superior relativa adoptada","value":-1,"unit":"m","source":"JC1 / DZ","status":"documentada / separación por material"}],"geometry":[{"label":"Extensión de la malla en X","value":1.239573,"unit":"m","source":"Geometría releída del IFC; datum absoluto de proceso provisional","status":"derivado"},{"label":"Extensión de la malla en Y","value":1.239573,"unit":"m","source":"Geometría releída del IFC; datum absoluto de proceso provisional","status":"derivado"},{"label":"Extensión de la malla en Z","value":0.5,"unit":"m","source":"Geometría releída del IFC; datum absoluto de proceso provisional","status":"derivado"},{"label":"Cota inferior de visualización","value":284.6,"unit":"m","source":"Geometría releída del IFC; datum absoluto de proceso provisional","status":"derivado"},{"label":"Cota superior de visualización","value":285.1,"unit":"m","source":"Geometría releída del IFC; datum absoluto de proceso provisional","status":"derivado"}]} | {"documentId":"LHD2609-JG00100-20260904","title":"Cimentaciones de equipos y pedestales del fabricante · revisión recibida 04/09/2026","date":"2026-09-04","sheet":"JC1 / DZ","fileName":"LHD2609-JG00100_20260904.dwg","revisionCaveat":"Fecha de revisión tomada del nombre recibido; cajetines internos mantienen 02/07/2026 y algunos textos de plantilla.","sourceFileSha256":"b42eb027b7bc0b14c38d1d13514f4899b58a732aa8d0ba2ccf10fa2fc3192890"} | provisional | [] | {"Cota inferior relativa (m)":-1.5,"Cota superior relativa (m)":-1,"Cero absoluto de visualización (m)":286.1,"Estado del cero absoluto":"Provisional","Criterio":"Las cotas relativas proceden del dibujo; la equivalencia absoluta no está confirmada."} | {"boundingBoxM":{"min":[36.044154,55.27302,-0.4],"max":[37.283727,56.512593,0.1]},"extentsM":[1.239573,1.239573,0.5],"meshSurfaceM2":4.62,"meshVolumeM3":0.605,"closedSolid":true,"basis":"Magnitudes de las mallas representadas, no cantidades certificadas de obra, compra o fabricación. Las partes pueden compartir superficies; no se suman como un despiece de materiales."} | {"profileId":"concrete_ha30","name":"Hormigón HA-30","materialName":"Hormigón HA-30","physicalMaterialStatus":"documentado","physicalMaterialSource":"Nota general de pedestales 2CED5","appearanceStatus":"criterio_visual","appearanceBasis":"Interpretación visual del material documental; el acabado, tono y parámetros PBR no son una especificación contractual.","note":"La apariencia gráfica no modifica ni confirma la especificación física del material."} | {"elementId":"found_0904_03329acbed84e5","ifcGuid":"2A66d1BD9Hg9Xe1qBVXbQU","ifcClass":"IfcFooting","buildingId":"process_plant","buildingName":"Zona de separación de aire","sourceDocumentId":"LHD2609-JG00100-20260904","sourceRepresentationKind":"foundation"} | {"layerId":"foundations","layerName":"Cimentaciones","role":"Cimentación industrial","basis":"Clasificación por función del elemento; no modifica las especificaciones documentales."} | {"profileId":"concrete_ha30","name":"Hormigón HA-30","status":"criterio_visual","basis":"Interpretación visual del material documental; el acabado, tono y parámetros PBR no son una especificación contractual.","physicalMaterialUnchanged":true} | 0.605 | Hormigón HA-30 | Hormigón HA-30 | found_0904_03329acbed84e5 | Nota general de pedestales 2CED5 | documentado | concrete_ha30 | [0.658824,0.658824,0.623529] | 0.94 | Zona de separación de aire; BIM · Cimentaciones | 1.23957 | 1.23957 | 0.5 | 284.6 | 285.1 | SUP-C16 | [] | ["C16"] | JC1 / DZ | ["2CCA0","2CD4D","2CCBF","2CD8D","2CCAE","2CCAF","2CD72","2CEF4","2CEF3"] | SUP-C16/Cimentación de marquesina C16 · cuerpo de hormigón | foundation | Geometría de fabricante; implantación absoluta provisional |  | Cimentaciones de equipos y pedestales del fabricante · revisión recibida 04/09/2026 | 2CCA0, 2CD4D, 2CCBF, 2CD8D, 2CCAE, 2CCAF, 2CD72, 2CEF4, 2CEF3 | -1.5 | -1 | 1.21 | Cotas relativas del dibujo. La equivalencia con un datum absoluto está pendiente. | Z del modelo = cota relativa + 1,10 m. Correspondencia provisional con 286,10 m; no es cota de obra confirmada. | Contornos y sección documentados por el fabricante | 1.1 | 1.1 | Material: Hormigón HA-30
Cimentación de marquesina C16 · pedestal de hormigón | Parcela industrial Jinhong | Cimentación industrial | Cimentaciones de equipos y pedestales del fabricante · revisión recibida 04/09/2026 | 0.563442 | 0.563442 | 1.2 | 2.9 | 0.3 | process_plant | Zona de separación de aire | {"name":"Hormigón HA-30","status":"documentado","source":"Nota general de pedestales 2CED5"} | {"documented":[{"label":"Extensión local X","value":0.5,"unit":"m","source":"2CCA0, 2CD4D, 2CCBF, 2CD8D, 2CCAE, 2CCAF, 2CD72, 2CEF4, 2CEF3","status":"derivada del contorno CAD"},{"label":"Extensión local Y","value":0.5,"unit":"m","source":"2CCA0, 2CD4D, 2CCBF, 2CD8D, 2CCAE, 2CCAF, 2CD72, 2CEF4, 2CEF3","status":"derivada del contorno CAD"},{"label":"Cota inferior relativa adoptada","value":-1,"unit":"m","source":"JC1 / DZ","status":"documentada"},{"label":"Cota superior relativa adoptada","value":0.2,"unit":"m","source":"JC1 / DZ","status":"documentada / separación por material"}],"geometry":[{"label":"Extensión de la malla en X","value":0.563442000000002,"unit":"m","source":"Geometría releída del IFC; datum absoluto de proceso provisional","status":"derivado"},{"label":"Extensión de la malla en Y","value":0.563442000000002,"unit":"m","source":"Geometría releída del IFC; datum absoluto de proceso provisional","status":"derivado"},{"label":"Extensión de la malla en Z","value":1.2,"unit":"m","source":"Geometría releída del IFC; datum absoluto de proceso provisional","status":"derivado"},{"label":"Cota inferior de visualización","value":285.1,"unit":"m","source":"Geometría releída del IFC; datum absoluto de proceso provisional","status":"derivado"},{"label":"Cota superior de visualización","value":286.3,"unit":"m","source":"Geometría releída del IFC; datum absoluto de proceso provisional","status":"derivado"}]} | {"documentId":"LHD2609-JG00100-20260904","title":"Cimentaciones de equipos y pedestales del fabricante · revisión recibida 04/09/2026","date":"2026-09-04","sheet":"JC1 / DZ","fileName":"LHD2609-JG00100_20260904.dwg","revisionCaveat":"Fecha de revisión tomada del nombre recibido; cajetines internos mantienen 02/07/2026 y algunos textos de plantilla.","sourceFileSha256":"b42eb027b7bc0b14c38d1d13514f4899b58a732aa8d0ba2ccf10fa2fc3192890"} | provisional | [] | {"Cota inferior relativa (m)":-1,"Cota superior relativa (m)":0.2,"Cero absoluto de visualización (m)":286.1,"Estado del cero absoluto":"Provisional","Criterio":"Las cotas relativas proceden del dibujo; la equivalencia absoluta no está confirmada."} | {"boundingBoxM":{"min":[36.38222,55.611086,0.1],"max":[36.945662,56.174528,1.3]},"extentsM":[0.563442,0.563442,1.2],"meshSurfaceM2":2.9,"meshVolumeM3":0.3,"closedSolid":true,"basis":"Magnitudes de las mallas representadas, no cantidades certificadas de obra, compra o fabricación. Las partes pueden compartir superficies; no se suman como un despiece de materiales."} | {"profileId":"concrete_ha30","name":"Hormigón HA-30","materialName":"Hormigón HA-30","physicalMaterialStatus":"documentado","physicalMaterialSource":"Nota general de pedestales 2CED5","appearanceStatus":"criterio_visual","appearanceBasis":"Interpretación visual del material documental; el acabado, tono y parámetros PBR no son una especificación contractual.","note":"La apariencia gráfica no modifica ni confirma la especificación física del material."} | {"elementId":"found_0904_1874f9bdf98b8a","ifcGuid":"1r3DE9ZgLTRQkLClbcFQQO","ifcClass":"IfcFooting","buildingId":"process_plant","buildingName":"Zona de separación de aire","sourceDocumentId":"LHD2609-JG00100-20260904","sourceRepresentationKind":"foundation"} | {"layerId":"foundations","layerName":"Cimentaciones","role":"Cimentación industrial","basis":"Clasificación por función del elemento; no modifica las especificaciones documentales."} | {"profileId":"concrete_ha30","name":"Hormigón HA-30","status":"criterio_visual","basis":"Interpretación visual del material documental; el acabado, tono y parámetros PBR no son una especificación contractual.","physicalMaterialUnchanged":true} | 0.3 | Hormigón HA-30 | Hormigón HA-30 | found_0904_1874f9bdf98b8a | Nota general de pedestales 2CED5 | documentado | concrete_ha30 | [0.658824,0.658824,0.623529] | 0.94 | Zona de separación de aire; BIM · Cimentaciones | 0.563442 | 0.563442 | 1.2 | 285.1 | 286.3 | SUP-C16 | [] | ["C16"] | JC1 / DZ | ["2CCA0","2CD4D","2CCBF","2CD8D","2CCAE","2CCAF","2CD72","2CEF4","2CEF3"] | SUP-C16/Cimentación de marquesina C16 · pedestal de hormigón | foundation | Geometría de fabricante; implantación absoluta provisional |  | Cimentaciones de equipos y pedestales del fabricante · revisión recibida 04/09/2026 | 2CCA0, 2CD4D, 2CCBF, 2CD8D, 2CCAE, 2CCAF, 2CD72, 2CEF4, 2CEF3 | -1 | 0.2 | 0.25 | Cotas relativas del dibujo. La equivalencia con un datum absoluto está pendiente. | Z del modelo = cota relativa + 1,10 m. Correspondencia provisional con 286,10 m; no es cota de obra confirmada. | Contornos y sección documentados por el fabricante | 0.5 | 0.5 | Material: Hormigón HA-30
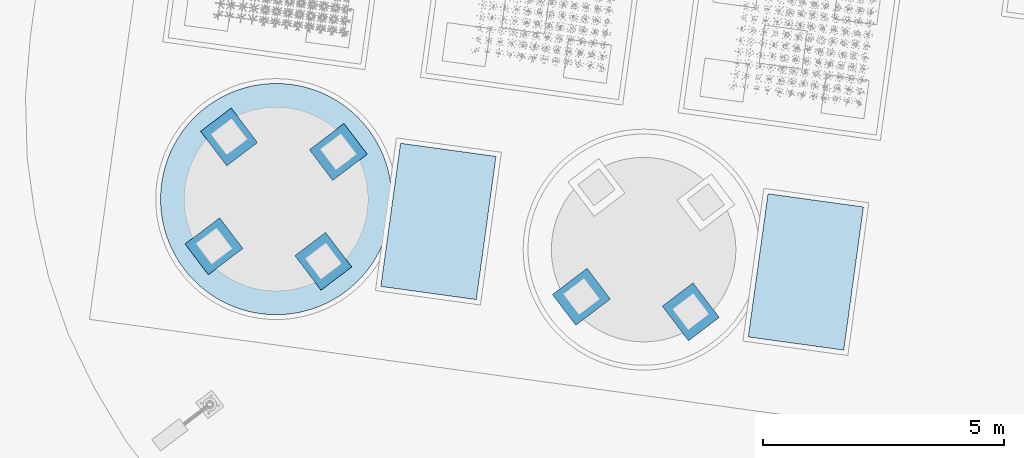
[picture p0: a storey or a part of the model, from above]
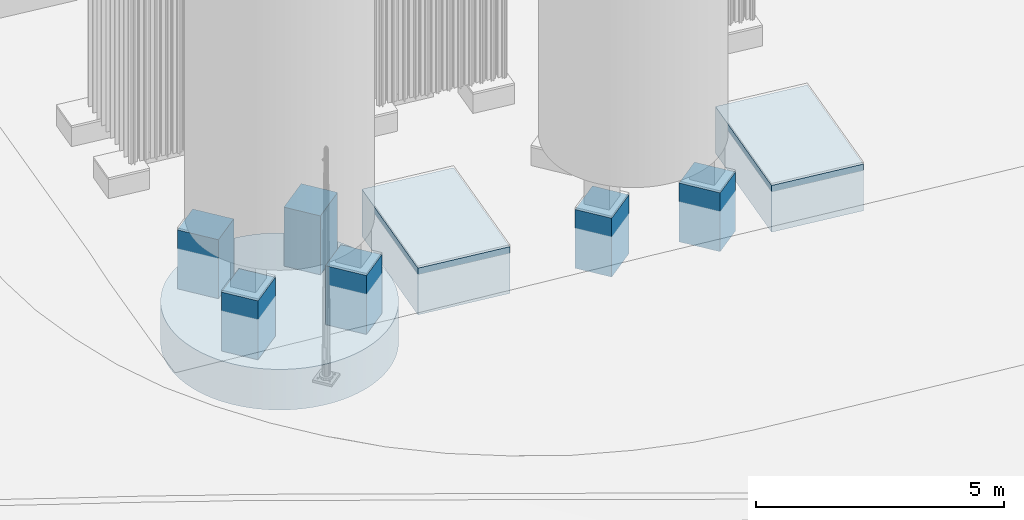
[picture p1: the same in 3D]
Properties of the parts of a building model (IFC4), part 81 of 134

# IfcFooting (214)
Name | In | Description = category = Categoria = Funcion | Document | ExtensionX (m) | ExtensionY (m) | ExtensionZ (m) | SuperficieDeLaMalla (m2) | VolumenGeometrico (m3) | buildingId | buildingName | material | dimensions | JH_InformacionBIM, source = DocumentoFuente | JH_InformacionBIM, status = EstadoDeInformacion | issues = IncidenciasPendientes | positioning = PosicionYEstado | geometryMetrics | materialAppearance | visualizationIdentity | classification | appearance | Volumen geométrico (m³) | JH_Trazabilidad, Material = name | Acabado de visualización = Acabado | Identificador | JH_EvidenciaDeMaterial, source | JH_EvidenciaDeMaterial, status | Perfil | ColorRGB | Rugosidad | Group | Extensión de la malla en X (m) | Extensión de la malla en Y (m) | Extensión de la malla en Z (m) = Espesor o altura real de sección (m) | Cota inferior de visualización (m) | Cota superior de visualización (m) | assemblyId = Conjunto de cimentación | equipmentIds | supportPositionIds | sectionRef = Sección de referencia | sourceCadHandles | stableElementKey | representationKind | geometryStatus | Equipos asociados | Documento de origen | Identificadores CAD de referencia | Cota inferior relativa (m) = Cota inferior relativa adoptada (m) | Cota superior relativa (m) = Cota superior relativa adoptada (m) | Área de planta (m²) | Referencia vertical | Implantación para visualización | Estado de la geometría | Extensión local X (m) | Extensión local Y (m) | Incidencias de origen
Cimentación de marquesina C17 · cuerpo de hormigón | Parcela industrial Jinhong | Cimentación industrial | Cimentaciones de equipos y pedestales del fabricante · revisión recibida 04/09/2026 | 1.23957 | 1.23957 | 0.5 | 4.62 | 0.605 | process_plant | Zona de separación de aire | {"name":"Hormigón HA-30","status":"documentado","source":"Nota general de pedestales 2CED5"} | {"documented":[{"label":"Extensión local X","value":1.1,"unit":"m","source":"2CCA1, 2CD4E, 2CCC0, 2CD8E, 2CCAB, 2CCAC, 2CD73, 2CEF6, 2CEF5","status":"derivada del contorno CAD"},{"label":"Extensión local Y","value":1.1,"unit":"m","source":"2CCA1, 2CD4E, 2CCC0, 2CD8E, 2CCAB, 2CCAC, 2CD73, 2CEF6, 2CEF5","status":"derivada del contorno CAD"},{"label":"Cota inferior relativa adoptada","value":-1.5,"unit":"m","source":"JC1 / DZ","status":"documentada"},{"label":"Cota superior relativa adoptada","value":-1,"unit":"m","source":"JC1 / DZ","status":"documentada / separación por material"}],"geometry":[{"label":"Extensión de la malla en X","value":1.239573,"unit":"m","source":"Geometría releída del IFC; datum absoluto de proceso provisional","status":"derivado"},{"label":"Extensión de la malla en Y","value":1.2395739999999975,"unit":"m","source":"Geometría releída del IFC; datum absoluto de proceso provisional","status":"derivado"},{"label":"Extensión de la malla en Z","value":0.5,"unit":"m","source":"Geometría releída del IFC; datum absoluto de proceso provisional","status":"derivado"},{"label":"Cota inferior de visualización","value":284.6,"unit":"m","source":"Geometría releída del IFC; datum absoluto de proceso provisional","status":"derivado"},{"label":"Cota superior de visualización","value":285.1,"unit":"m","source":"Geometría releída del IFC; datum absoluto de proceso provisional","status":"derivado"}]} | {"documentId":"LHD2609-JG00100-20260904","title":"Cimentaciones de equipos y pedestales del fabricante · revisión recibida 04/09/2026","date":"2026-09-04","sheet":"JC1 / DZ","fileName":"LHD2609-JG00100_20260904.dwg","revisionCaveat":"Fecha de revisión tomada del nombre recibido; cajetines internos mantienen 02/07/2026 y algunos textos de plantilla.","sourceFileSha256":"b42eb027b7bc0b14c38d1d13514f4899b58a732aa8d0ba2ccf10fa2fc3192890"} | provisional | [] | {"Cota inferior relativa (m)":-1.5,"Cota superior relativa (m)":-1,"Cero absoluto de visualización (m)":286.1,"Estado del cero absoluto":"Provisional","Criterio":"Las cotas relativas proceden del dibujo; la equivalencia absoluta no está confirmada."} | {"boundingBoxM":{"min":[42.193767,57.051997,-0.4],"max":[43.43334,58.291571,0.1]},"extentsM":[1.239573,1.239574,0.5],"meshSurfaceM2":4.620001,"meshVolumeM3":0.605,"closedSolid":true,"basis":"Magnitudes de las mallas representadas, no cantidades certificadas de obra, compra o fabricación. Las partes pueden compartir superficies; no se suman como un despiece de materiales."} | {"profileId":"concrete_ha30","name":"Hormigón HA-30","materialName":"Hormigón HA-30","physicalMaterialStatus":"documentado","physicalMaterialSource":"Nota general de pedestales 2CED5","appearanceStatus":"criterio_visual","appearanceBasis":"Interpretación visual del material documental; el acabado, tono y parámetros PBR no son una especificación contractual.","note":"La apariencia gráfica no modifica ni confirma la especificación física del material."} | {"elementId":"found_0904_f6dc1899e082bf","ifcGuid":"1AU0Ya2R5MggZy6mhkSpud","ifcClass":"IfcFooting","buildingId":"process_plant","buildingName":"Zona de separación de aire","sourceDocumentId":"LHD2609-JG00100-20260904","sourceRepresentationKind":"foundation"} | {"layerId":"foundations","layerName":"Cimentaciones","role":"Cimentación industrial","basis":"Clasificación por función del elemento; no modifica las especificaciones documentales."} | {"profileId":"concrete_ha30","name":"Hormigón HA-30","status":"criterio_visual","basis":"Interpretación visual del material documental; el acabado, tono y parámetros PBR no son una especificación contractual.","physicalMaterialUnchanged":true} | 0.605 | Hormigón HA-30 | Hormigón HA-30 | found_0904_f6dc1899e082bf | Nota general de pedestales 2CED5 | documentado | concrete_ha30 | [0.658824,0.658824,0.623529] | 0.94 | Zona de separación de aire; BIM · Cimentaciones | 1.23957 | 1.23957 | 0.5 | 284.6 | 285.1 | SUP-C17 | [] | ["C17"] | JC1 / DZ | ["2CCA1","2CD4E","2CCC0","2CD8E","2CCAB","2CCAC","2CD73","2CEF6","2CEF5"] | SUP-C17/Cimentación de marquesina C17 · cuerpo de hormigón | foundation | Geometría de fabricante; implantación absoluta provisional |  | Cimentaciones de equipos y pedestales del fabricante · revisión recibida 04/09/2026 | 2CCA1, 2CD4E, 2CCC0, 2CD8E, 2CCAB, 2CCAC, 2CD73, 2CEF6, 2CEF5 | -1.5 | -1 | 1.21 | Cotas relativas del dibujo. La equivalencia con un datum absoluto está pendiente. | Z del modelo = cota relativa + 1,10 m. Correspondencia provisional con 286,10 m; no es cota de obra confirmada. | Contornos y sección documentados por el fabricante | 1.1 | 1.1 | Material: Hormigón HA-30
Cimentación de marquesina C17 · pedestal de hormigón | Parcela industrial Jinhong | Cimentación industrial | Cimentaciones de equipos y pedestales del fabricante · revisión recibida 04/09/2026 | 0.563442 | 0.563442 | 1.2 | 2.9 | 0.3 | process_plant | Zona de separación de aire | {"name":"Hormigón HA-30","status":"documentado","source":"Nota general de pedestales 2CED5"} | {"documented":[{"label":"Extensión local X","value":0.5,"unit":"m","source":"2CCA1, 2CD4E, 2CCC0, 2CD8E, 2CCAB, 2CCAC, 2CD73, 2CEF6, 2CEF5","status":"derivada del contorno CAD"},{"label":"Extensión local Y","value":0.5,"unit":"m","source":"2CCA1, 2CD4E, 2CCC0, 2CD8E, 2CCAB, 2CCAC, 2CD73, 2CEF6, 2CEF5","status":"derivada del contorno CAD"},{"label":"Cota inferior relativa adoptada","value":-1,"unit":"m","source":"JC1 / DZ","status":"documentada"},{"label":"Cota superior relativa adoptada","value":0.2,"unit":"m","source":"JC1 / DZ","status":"documentada / separación por material"}],"geometry":[{"label":"Extensión de la malla en X","value":0.563442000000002,"unit":"m","source":"Geometría releída del IFC; datum absoluto de proceso provisional","status":"derivado"},{"label":"Extensión de la malla en Y","value":0.563442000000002,"unit":"m","source":"Geometría releída del IFC; datum absoluto de proceso provisional","status":"derivado"},{"label":"Extensión de la malla en Z","value":1.2,"unit":"m","source":"Geometría releída del IFC; datum absoluto de proceso provisional","status":"derivado"},{"label":"Cota inferior de visualización","value":285.1,"unit":"m","source":"Geometría releída del IFC; datum absoluto de proceso provisional","status":"derivado"},{"label":"Cota superior de visualización","value":286.3,"unit":"m","source":"Geometría releída del IFC; datum absoluto de proceso provisional","status":"derivado"}]} | {"documentId":"LHD2609-JG00100-20260904","title":"Cimentaciones de equipos y pedestales del fabricante · revisión recibida 04/09/2026","date":"2026-09-04","sheet":"JC1 / DZ","fileName":"LHD2609-JG00100_20260904.dwg","revisionCaveat":"Fecha de revisión tomada del nombre recibido; cajetines internos mantienen 02/07/2026 y algunos textos de plantilla.","sourceFileSha256":"b42eb027b7bc0b14c38d1d13514f4899b58a732aa8d0ba2ccf10fa2fc3192890"} | provisional | [] | {"Cota inferior relativa (m)":-1,"Cota superior relativa (m)":0.2,"Cero absoluto de visualización (m)":286.1,"Estado del cero absoluto":"Provisional","Criterio":"Las cotas relativas proceden del dibujo; la equivalencia absoluta no está confirmada."} | {"boundingBoxM":{"min":[42.531833,57.390063,0.1],"max":[43.095275,57.953505,1.3]},"extentsM":[0.563442,0.563442,1.2],"meshSurfaceM2":2.899999,"meshVolumeM3":0.3,"closedSolid":true,"basis":"Magnitudes de las mallas representadas, no cantidades certificadas de obra, compra o fabricación. Las partes pueden compartir superficies; no se suman como un despiece de materiales."} | {"profileId":"concrete_ha30","name":"Hormigón HA-30","materialName":"Hormigón HA-30","physicalMaterialStatus":"documentado","physicalMaterialSource":"Nota general de pedestales 2CED5","appearanceStatus":"criterio_visual","appearanceBasis":"Interpretación visual del material documental; el acabado, tono y parámetros PBR no son una especificación contractual.","note":"La apariencia gráfica no modifica ni confirma la especificación física del material."} | {"elementId":"found_0904_be9c7e047eb303","ifcGuid":"0NVsYjLyHT1PSmOK2uobiy","ifcClass":"IfcFooting","buildingId":"process_plant","buildingName":"Zona de separación de aire","sourceDocumentId":"LHD2609-JG00100-20260904","sourceRepresentationKind":"foundation"} | {"layerId":"foundations","layerName":"Cimentaciones","role":"Cimentación industrial","basis":"Clasificación por función del elemento; no modifica las especificaciones documentales."} | {"profileId":"concrete_ha30","name":"Hormigón HA-30","status":"criterio_visual","basis":"Interpretación visual del material documental; el acabado, tono y parámetros PBR no son una especificación contractual.","physicalMaterialUnchanged":true} | 0.3 | Hormigón HA-30 | Hormigón HA-30 | found_0904_be9c7e047eb303 | Nota general de pedestales 2CED5 | documentado | concrete_ha30 | [0.658824,0.658824,0.623529] | 0.94 | Zona de separación de aire; BIM · Cimentaciones | 0.563442 | 0.563442 | 1.2 | 285.1 | 286.3 | SUP-C17 | [] | ["C17"] | JC1 / DZ | ["2CCA1","2CD4E","2CCC0","2CD8E","2CCAB","2CCAC","2CD73","2CEF6","2CEF5"] | SUP-C17/Cimentación de marquesina C17 · pedestal de hormigón | foundation | Geometría de fabricante; implantación absoluta provisional |  | Cimentaciones de equipos y pedestales del fabricante · revisión recibida 04/09/2026 | 2CCA1, 2CD4E, 2CCC0, 2CD8E, 2CCAB, 2CCAC, 2CD73, 2CEF6, 2CEF5 | -1 | 0.2 | 0.25 | Cotas relativas del dibujo. La equivalencia con un datum absoluto está pendiente. | Z del modelo = cota relativa + 1,10 m. Correspondencia provisional con 286,10 m; no es cota de obra confirmada. | Contornos y sección documentados por el fabricante | 0.5 | 0.5 | Material: Hormigón HA-30
Cimentación de marquesina C18 · cuerpo de hormigón | Parcela industrial Jinhong | Cimentación industrial | Cimentaciones de equipos y pedestales del fabricante · revisión recibida 04/09/2026 | 1.23957 | 1.23957 | 0.5 | 4.62 | 0.605 | process_plant | Zona de separación de aire | {"name":"Hormigón HA-30","status":"documentado","source":"Nota general de pedestales 2CED5"} | {"documented":[{"label":"Extensión local X","value":1.1,"unit":"m","source":"2CCA2, 2CD4F, 2CCC1, 2CD8F, 2CCAA, 2CCAD, 2CD74, 2CEF8, 2CEF7","status":"derivada del contorno CAD"},{"label":"Extensión local Y","value":1.1,"unit":"m","source":"2CCA2, 2CD4F, 2CCC1, 2CD8F, 2CCAA, 2CCAD, 2CD74, 2CEF8, 2CEF7","status":"derivada del contorno CAD"},{"label":"Cota inferior relativa adoptada","value":-1.5,"unit":"m","source":"JC1 / DZ","status":"documentada"},{"label":"Cota superior relativa adoptada","value":-1,"unit":"m","source":"JC1 / DZ","status":"documentada / separación por material"}],"geometry":[{"label":"Extensión de la malla en X","value":1.239573,"unit":"m","source":"Geometría releída del IFC; datum absoluto de proceso provisional","status":"derivado"},{"label":"Extensión de la malla en Y","value":1.239573,"unit":"m","source":"Geometría releída del IFC; datum absoluto de proceso provisional","status":"derivado"},{"label":"Extensión de la malla en Z","value":0.5,"unit":"m","source":"Geometría releída del IFC; datum absoluto de proceso provisional","status":"derivado"},{"label":"Cota inferior de visualización","value":284.6,"unit":"m","source":"Geometría releída del IFC; datum absoluto de proceso provisional","status":"derivado"},{"label":"Cota superior de visualización","value":285.1,"unit":"m","source":"Geometría releída del IFC; datum absoluto de proceso provisional","status":"derivado"}]} | {"documentId":"LHD2609-JG00100-20260904","title":"Cimentaciones de equipos y pedestales del fabricante · revisión recibida 04/09/2026","date":"2026-09-04","sheet":"JC1 / DZ","fileName":"LHD2609-JG00100_20260904.dwg","revisionCaveat":"Fecha de revisión tomada del nombre recibido; cajetines internos mantienen 02/07/2026 y algunos textos de plantilla.","sourceFileSha256":"b42eb027b7bc0b14c38d1d13514f4899b58a732aa8d0ba2ccf10fa2fc3192890"} | provisional | [] | {"Cota inferior relativa (m)":-1.5,"Cota superior relativa (m)":-1,"Cero absoluto de visualización (m)":286.1,"Estado del cero absoluto":"Provisional","Criterio":"Las cotas relativas proceden del dibujo; la equivalencia absoluta no está confirmada."} | {"boundingBoxM":{"min":[41.839637,54.476227,-0.4],"max":[43.07921,55.7158,0.1]},"extentsM":[1.239573,1.239573,0.5],"meshSurfaceM2":4.62,"meshVolumeM3":0.605,"closedSolid":true,"basis":"Magnitudes de las mallas representadas, no cantidades certificadas de obra, compra o fabricación. Las partes pueden compartir superficies; no se suman como un despiece de materiales."} | {"profileId":"concrete_ha30","name":"Hormigón HA-30","materialName":"Hormigón HA-30","physicalMaterialStatus":"documentado","physicalMaterialSource":"Nota general de pedestales 2CED5","appearanceStatus":"criterio_visual","appearanceBasis":"Interpretación visual del material documental; el acabado, tono y parámetros PBR no son una especificación contractual.","note":"La apariencia gráfica no modifica ni confirma la especificación física del material."} | {"elementId":"found_0904_53334971276752","ifcGuid":"1OjX5fwWLQsvKitdfeLMJH","ifcClass":"IfcFooting","buildingId":"process_plant","buildingName":"Zona de separación de aire","sourceDocumentId":"LHD2609-JG00100-20260904","sourceRepresentationKind":"foundation"} | {"layerId":"foundations","layerName":"Cimentaciones","role":"Cimentación industrial","basis":"Clasificación por función del elemento; no modifica las especificaciones documentales."} | {"profileId":"concrete_ha30","name":"Hormigón HA-30","status":"criterio_visual","basis":"Interpretación visual del material documental; el acabado, tono y parámetros PBR no son una especificación contractual.","physicalMaterialUnchanged":true} | 0.605 | Hormigón HA-30 | Hormigón HA-30 | found_0904_53334971276752 | Nota general de pedestales 2CED5 | documentado | concrete_ha30 | [0.658824,0.658824,0.623529] | 0.94 | Zona de separación de aire; BIM · Cimentaciones | 1.23957 | 1.23957 | 0.5 | 284.6 | 285.1 | SUP-C18 | [] | ["C18"] | JC1 / DZ | ["2CCA2","2CD4F","2CCC1","2CD8F","2CCAA","2CCAD","2CD74","2CEF8","2CEF7"] | SUP-C18/Cimentación de marquesina C18 · cuerpo de hormigón | foundation | Geometría de fabricante; implantación absoluta provisional |  | Cimentaciones de equipos y pedestales del fabricante · revisión recibida 04/09/2026 | 2CCA2, 2CD4F, 2CCC1, 2CD8F, 2CCAA, 2CCAD, 2CD74, 2CEF8, 2CEF7 | -1.5 | -1 | 1.21 | Cotas relativas del dibujo. La equivalencia con un datum absoluto está pendiente. | Z del modelo = cota relativa + 1,10 m. Correspondencia provisional con 286,10 m; no es cota de obra confirmada. | Contornos y sección documentados por el fabricante | 1.1 | 1.1 | Material: Hormigón HA-30
Cimentación de marquesina C18 · pedestal de hormigón | Parcela industrial Jinhong | Cimentación industrial | Cimentaciones de equipos y pedestales del fabricante · revisión recibida 04/09/2026 | 0.563443 | 0.563442 | 1.2 | 2.9 | 0.3 | process_plant | Zona de separación de aire | {"name":"Hormigón HA-30","status":"documentado","source":"Nota general de pedestales 2CED5"} | {"documented":[{"label":"Extensión local X","value":0.5,"unit":"m","source":"2CCA2, 2CD4F, 2CCC1, 2CD8F, 2CCAA, 2CCAD, 2CD74, 2CEF8, 2CEF7","status":"derivada del contorno CAD"},{"label":"Extensión local Y","value":0.5,"unit":"m","source":"2CCA2, 2CD4F, 2CCC1, 2CD8F, 2CCAA, 2CCAD, 2CD74, 2CEF8, 2CEF7","status":"derivada del contorno CAD"},{"label":"Cota inferior relativa adoptada","value":-1,"unit":"m","source":"JC1 / DZ","status":"documentada"},{"label":"Cota superior relativa adoptada","value":0.2,"unit":"m","source":"JC1 / DZ","status":"documentada / separación por material"}],"geometry":[{"label":"Extensión de la malla en X","value":0.5634430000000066,"unit":"m","source":"Geometría releída del IFC; datum absoluto de proceso provisional","status":"derivado"},{"label":"Extensión de la malla en Y","value":0.563442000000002,"unit":"m","source":"Geometría releída del IFC; datum absoluto de proceso provisional","status":"derivado"},{"label":"Extensión de la malla en Z","value":1.2,"unit":"m","source":"Geometría releída del IFC; datum absoluto de proceso provisional","status":"derivado"},{"label":"Cota inferior de visualización","value":285.1,"unit":"m","source":"Geometría releída del IFC; datum absoluto de proceso provisional","status":"derivado"},{"label":"Cota superior de visualización","value":286.3,"unit":"m","source":"Geometría releída del IFC; datum absoluto de proceso provisional","status":"derivado"}]} | {"documentId":"LHD2609-JG00100-20260904","title":"Cimentaciones de equipos y pedestales del fabricante · revisión recibida 04/09/2026","date":"2026-09-04","sheet":"JC1 / DZ","fileName":"LHD2609-JG00100_20260904.dwg","revisionCaveat":"Fecha de revisión tomada del nombre recibido; cajetines internos mantienen 02/07/2026 y algunos textos de plantilla.","sourceFileSha256":"b42eb027b7bc0b14c38d1d13514f4899b58a732aa8d0ba2ccf10fa2fc3192890"} | provisional | [] | {"Cota inferior relativa (m)":-1,"Cota superior relativa (m)":0.2,"Cero absoluto de visualización (m)":286.1,"Estado del cero absoluto":"Provisional","Criterio":"Las cotas relativas proceden del dibujo; la equivalencia absoluta no está confirmada."} | {"boundingBoxM":{"min":[42.177702,54.814293,0.1],"max":[42.741145,55.377735,1.3]},"extentsM":[0.563443,0.563442,1.2],"meshSurfaceM2":2.900001,"meshVolumeM3":0.3,"closedSolid":true,"basis":"Magnitudes de las mallas representadas, no cantidades certificadas de obra, compra o fabricación. Las partes pueden compartir superficies; no se suman como un despiece de materiales."} | {"profileId":"concrete_ha30","name":"Hormigón HA-30","materialName":"Hormigón HA-30","physicalMaterialStatus":"documentado","physicalMaterialSource":"Nota general de pedestales 2CED5","appearanceStatus":"criterio_visual","appearanceBasis":"Interpretación visual del material documental; el acabado, tono y parámetros PBR no son una especificación contractual.","note":"La apariencia gráfica no modifica ni confirma la especificación física del material."} | {"elementId":"found_0904_6afe67f6d2a8a6","ifcGuid":"11fGpkegnQKOmzU1E0o8GJ","ifcClass":"IfcFooting","buildingId":"process_plant","buildingName":"Zona de separación de aire","sourceDocumentId":"LHD2609-JG00100-20260904","sourceRepresentationKind":"foundation"} | {"layerId":"foundations","layerName":"Cimentaciones","role":"Cimentación industrial","basis":"Clasificación por función del elemento; no modifica las especificaciones documentales."} | {"profileId":"concrete_ha30","name":"Hormigón HA-30","status":"criterio_visual","basis":"Interpretación visual del material documental; el acabado, tono y parámetros PBR no son una especificación contractual.","physicalMaterialUnchanged":true} | 0.3 | Hormigón HA-30 | Hormigón HA-30 | found_0904_6afe67f6d2a8a6 | Nota general de pedestales 2CED5 | documentado | concrete_ha30 | [0.658824,0.658824,0.623529] | 0.94 | Zona de separación de aire; BIM · Cimentaciones | 0.563443 | 0.563442 | 1.2 | 285.1 | 286.3 | SUP-C18 | [] | ["C18"] | JC1 / DZ | ["2CCA2","2CD4F","2CCC1","2CD8F","2CCAA","2CCAD","2CD74","2CEF8","2CEF7"] | SUP-C18/Cimentación de marquesina C18 · pedestal de hormigón | foundation | Geometría de fabricante; implantación absoluta provisional |  | Cimentaciones de equipos y pedestales del fabricante · revisión recibida 04/09/2026 | 2CCA2, 2CD4F, 2CCC1, 2CD8F, 2CCAA, 2CCAD, 2CD74, 2CEF8, 2CEF7 | -1 | 0.2 | 0.25 | Cotas relativas del dibujo. La equivalencia con un datum absoluto está pendiente. | Z del modelo = cota relativa + 1,10 m. Correspondencia provisional con 286,10 m; no es cota de obra confirmada. | Contornos y sección documentados por el fabricante | 0.5 | 0.5 | Material: Hormigón HA-30
Cimentación de soporte de tuberías C19 · cuerpo de hormigón | Parcela industrial Jinhong | Cimentación industrial | Cimentaciones de equipos y pedestales del fabricante · revisión recibida 04/09/2026 | 1.12688 | 1.12688 | 0.4 | 3.6 | 0.4 | process_plant | Zona de separación de aire | {"name":"Hormigón HA-30","status":"documentado","source":"Nota general de pedestales 2CED5"} | {"documented":[{"label":"Extensión local X","value":1.0,"unit":"m","source":"2CCA3, 2CD50, 2CCC2, 2CD90, 2CCB2, 2CCB4, 2CD75, 2CEB5, 2CE90","status":"derivada del contorno CAD"},{"label":"Extensión local Y","value":1.0,"unit":"m","source":"2CCA3, 2CD50, 2CCC2, 2CD90, 2CCB2, 2CCB4, 2CD75, 2CEB5, 2CE90","status":"derivada del contorno CAD"},{"label":"Cota inferior relativa adoptada","value":-1.0,"unit":"m","source":"ZD1 / DZ-1","status":"documentada"},{"label":"Cota superior relativa adoptada","value":-0.6,"unit":"m","source":"ZD1 / DZ-1","status":"documentada / separación por material"}],"geometry":[{"label":"Extensión de la malla en X","value":1.1268849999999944,"unit":"m","source":"Geometría releída del IFC; datum absoluto de proceso provisional","status":"derivado"},{"label":"Extensión de la malla en Y","value":1.1268849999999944,"unit":"m","source":"Geometría releída del IFC; datum absoluto de proceso provisional","status":"derivado"},{"label":"Extensión de la malla en Z","value":0.4,"unit":"m","source":"Geometría releída del IFC; datum absoluto de proceso provisional","status":"derivado"},{"label":"Cota inferior de visualización","value":285.1,"unit":"m","source":"Geometría releída del IFC; datum absoluto de proceso provisional","status":"derivado"},{"label":"Cota superior de visualización","value":285.5,"unit":"m","source":"Geometría releída del IFC; datum absoluto de proceso provisional","status":"derivado"}]} | {"documentId":"LHD2609-JG00100-20260904","title":"Cimentaciones de equipos y pedestales del fabricante · revisión recibida 04/09/2026","date":"2026-09-04","sheet":"ZD1 / DZ-1","fileName":"LHD2609-JG00100_20260904.dwg","revisionCaveat":"Fecha de revisión tomada del nombre recibido; cajetines internos mantienen 02/07/2026 y algunos textos de plantilla.","sourceFileSha256":"b42eb027b7bc0b14c38d1d13514f4899b58a732aa8d0ba2ccf10fa2fc3192890"} | provisional | [] | {"Cota inferior relativa (m)":-1.0,"Cota superior relativa (m)":-0.6,"Cero absoluto de visualización (m)":286.1,"Estado del cero absoluto":"Provisional","Criterio":"Las cotas relativas proceden del dibujo; la equivalencia absoluta no está confirmada."} | {"boundingBoxM":{"min":[42.595657,53.931673,0.1],"max":[43.722542,55.058558,0.5]},"extentsM":[1.126885,1.126885,0.4],"meshSurfaceM2":3.600001,"meshVolumeM3":0.4,"closedSolid":true,"basis":"Magnitudes de las mallas representadas, no cantidades certificadas de obra, compra o fabricación. Las partes pueden compartir superficies; no se suman como un despiece de materiales."} | {"profileId":"concrete_ha30","name":"Hormigón HA-30","materialName":"Hormigón HA-30","physicalMaterialStatus":"documentado","physicalMaterialSource":"Nota general de pedestales 2CED5","appearanceStatus":"criterio_visual","appearanceBasis":"Interpretación visual del material documental; el acabado, tono y parámetros PBR no son una especificación contractual.","note":"La apariencia gráfica no modifica ni confirma la especificación física del material."} | {"elementId":"found_0904_e9687c2365da2a","ifcGuid":"1olSoHF3fVswkpNPxdsHCs","ifcClass":"IfcFooting","buildingId":"process_plant","buildingName":"Zona de separación de aire","sourceDocumentId":"LHD2609-JG00100-20260904","sourceRepresentationKind":"foundation"} | {"layerId":"foundations","layerName":"Cimentaciones","role":"Cimentación industrial","basis":"Clasificación por función del elemento; no modifica las especificaciones documentales."} | {"profileId":"concrete_ha30","name":"Hormigón HA-30","status":"criterio_visual","basis":"Interpretación visual del material documental; el acabado, tono y parámetros PBR no son una especificación contractual.","physicalMaterialUnchanged":true} | 0.4 | Hormigón HA-30 | Hormigón HA-30 | found_0904_e9687c2365da2a | Nota general de pedestales 2CED5 | documentado | concrete_ha30 | [0.658824,0.658824,0.623529] | 0.94 | Zona de separación de aire; BIM · Cimentaciones | 1.12688 | 1.12688 | 0.4 | 285.1 | 285.5 | SUP-C19 | [] | ["C19"] | ZD1 / DZ-1 | ["2CCA3","2CD50","2CCC2","2CD90","2CCB2","2CCB4","2CD75","2CEB5","2CE90"] | SUP-C19/Cimentación de soporte de tuberías C19 · cuerpo de hormigón | foundation | Geometría de fabricante; implantación absoluta provisional |  | Cimentaciones de equipos y pedestales del fabricante · revisión recibida 04/09/2026 | 2CCA3, 2CD50, 2CCC2, 2CD90, 2CCB2, 2CCB4, 2CD75, 2CEB5, 2CE90 | -1 | -0.6 | 1 | Cotas relativas del dibujo. La equivalencia con un datum absoluto está pendiente. | Z del modelo = cota relativa + 1,10 m. Correspondencia provisional con 286,10 m; no es cota de obra confirmada. | Contornos y sección documentados por el fabricante | 1 | 1 | Material: Hormigón HA-30
Cimentación de soporte de tuberías C19 · pedestal de hormigón | Parcela industrial Jinhong | Cimentación industrial | Cimentaciones de equipos y pedestales del fabricante · revisión recibida 04/09/2026 | 0.507098 | 0.507098 | 0.8 | 1.845 | 0.162 | process_plant | Zona de separación de aire | {"name":"Hormigón HA-30","status":"documentado","source":"Nota general de pedestales 2CED5"} | {"documented":[{"label":"Extensión local X","value":0.45,"unit":"m","source":"2CCA3, 2CD50, 2CCC2, 2CD90, 2CCB2, 2CCB4, 2CD75, 2CEB5, 2CE90","status":"derivada del contorno CAD"},{"label":"Extensión local Y","value":0.45,"unit":"m","source":"2CCA3, 2CD50, 2CCC2, 2CD90, 2CCB2, 2CCB4, 2CD75, 2CEB5, 2CE90","status":"derivada del contorno CAD"},{"label":"Cota inferior relativa adoptada","value":-0.6,"unit":"m","source":"ZD1 / DZ-1","status":"documentada"},{"label":"Cota superior relativa adoptada","value":0.2,"unit":"m","source":"ZD1 / DZ-1","status":"documentada / separación por material"}],"geometry":[{"label":"Extensión de la malla en X","value":0.5070979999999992,"unit":"m","source":"Geometría releída del IFC; datum absoluto de proceso provisional","status":"derivado"},{"label":"Extensión de la malla en Y","value":0.5070979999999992,"unit":"m","source":"Geometría releída del IFC; datum absoluto de proceso provisional","status":"derivado"},{"label":"Extensión de la malla en Z","value":0.8,"unit":"m","source":"Geometría releída del IFC; datum absoluto de proceso provisional","status":"derivado"},{"label":"Cota inferior de visualización","value":285.5,"unit":"m","source":"Geometría releída del IFC; datum absoluto de proceso provisional","status":"derivado"},{"label":"Cota superior de visualización","value":286.3,"unit":"m","source":"Geometría releída del IFC; datum absoluto de proceso provisional","status":"derivado"}]} | {"documentId":"LHD2609-JG00100-20260904","title":"Cimentaciones de equipos y pedestales del fabricante · revisión recibida 04/09/2026","date":"2026-09-04","sheet":"ZD1 / DZ-1","fileName":"LHD2609-JG00100_20260904.dwg","revisionCaveat":"Fecha de revisión tomada del nombre recibido; cajetines internos mantienen 02/07/2026 y algunos textos de plantilla.","sourceFileSha256":"b42eb027b7bc0b14c38d1d13514f4899b58a732aa8d0ba2ccf10fa2fc3192890"} | provisional | [] | {"Cota inferior relativa (m)":-0.6,"Cota superior relativa (m)":0.2,"Cero absoluto de visualización (m)":286.1,"Estado del cero absoluto":"Provisional","Criterio":"Las cotas relativas proceden del dibujo; la equivalencia absoluta no está confirmada."} | {"boundingBoxM":{"min":[42.90555,54.241566,0.5],"max":[43.412648,54.748664,1.3]},"extentsM":[0.507098,0.507098,0.8],"meshSurfaceM2":1.844999,"meshVolumeM3":0.162,"closedSolid":true,"basis":"Magnitudes de las mallas representadas, no cantidades certificadas de obra, compra o fabricación. Las partes pueden compartir superficies; no se suman como un despiece de materiales."} | {"profileId":"concrete_ha30","name":"Hormigón HA-30","materialName":"Hormigón HA-30","physicalMaterialStatus":"documentado","physicalMaterialSource":"Nota general de pedestales 2CED5","appearanceStatus":"criterio_visual","appearanceBasis":"Interpretación visual del material documental; el acabado, tono y parámetros PBR no son una especificación contractual.","note":"La apariencia gráfica no modifica ni confirma la especificación física del material."} | {"elementId":"found_0904_9b11067b842f4c","ifcGuid":"14zTHmR29OUhsJyPQHG$ee","ifcClass":"IfcFooting","buildingId":"process_plant","buildingName":"Zona de separación de aire","sourceDocumentId":"LHD2609-JG00100-20260904","sourceRepresentationKind":"foundation"} | {"layerId":"foundations","layerName":"Cimentaciones","role":"Cimentación industrial","basis":"Clasificación por función del elemento; no modifica las especificaciones documentales."} | {"profileId":"concrete_ha30","name":"Hormigón HA-30","status":"criterio_visual","basis":"Interpretación visual del material documental; el acabado, tono y parámetros PBR no son una especificación contractual.","physicalMaterialUnchanged":true} | 0.162 | Hormigón HA-30 | Hormigón HA-30 | found_0904_9b11067b842f4c | Nota general de pedestales 2CED5 | documentado | concrete_ha30 | [0.658824,0.658824,0.623529] | 0.94 | Zona de separación de aire; BIM · Cimentaciones | 0.507098 | 0.507098 | 0.8 | 285.5 | 286.3 | SUP-C19 | [] | ["C19"] | ZD1 / DZ-1 | ["2CCA3","2CD50","2CCC2","2CD90","2CCB2","2CCB4","2CD75","2CEB5","2CE90"] | SUP-C19/Cimentación de soporte de tuberías C19 · pedestal de hormigón | foundation | Geometría de fabricante; implantación absoluta provisional |  | Cimentaciones de equipos y pedestales del fabricante · revisión recibida 04/09/2026 | 2CCA3, 2CD50, 2CCC2, 2CD90, 2CCB2, 2CCB4, 2CD75, 2CEB5, 2CE90 | -0.6 | 0.2 | 0.2025 | Cotas relativas del dibujo. La equivalencia con un datum absoluto está pendiente. | Z del modelo = cota relativa + 1,10 m. Correspondencia provisional con 286,10 m; no es cota de obra confirmada. | Contornos y sección documentados por el fabricante | 0.45 | 0.45 | Material: Hormigón HA-30
Cimentación de soporte de tuberías C20 · cuerpo de hormigón | Parcela industrial Jinhong | Cimentación industrial | Cimentaciones de equipos y pedestales del fabricante · revisión recibida 04/09/2026 | 1.12689 | 1.12688 | 0.4 | 3.6 | 0.4 | process_plant | Zona de separación de aire | {"name":"Hormigón HA-30","status":"documentado","source":"Nota general de pedestales 2CED5"} | {"documented":[{"label":"Extensión local X","value":1.0,"unit":"m","source":"2CCA4, 2CD51, 2CCC3, 2CD91, 2CCB3, 2CCB5, 2CD76, 2CEB6, 2CE91","status":"derivada del contorno CAD"},{"label":"Extensión local Y","value":1.0,"unit":"m","source":"2CCA4, 2CD51, 2CCC3, 2CD91, 2CCB3, 2CCB5, 2CD76, 2CEB6, 2CE91","status":"derivada del contorno CAD"},{"label":"Cota inferior relativa adoptada","value":-1.0,"unit":"m","source":"ZD1 / DZ-1","status":"interpretación con conflicto conservado"},{"label":"Cota superior relativa adoptada","value":-0.6,"unit":"m","source":"ZD1 / DZ-1","status":"documentada / separación por material"}],"geometry":[{"label":"Extensión de la malla en X","value":1.1268850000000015,"unit":"m","source":"Geometría releída del IFC; datum absoluto de proceso provisional","status":"derivado"},{"label":"Extensión de la malla en Y","value":1.1268849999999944,"unit":"m","source":"Geometría releída del IFC; datum absoluto de proceso provisional","status":"derivado"},{"label":"Extensión de la malla en Z","value":0.4,"unit":"m","source":"Geometría releída del IFC; datum absoluto de proceso provisional","status":"derivado"},{"label":"Cota inferior de visualización","value":285.1,"unit":"m","source":"Geometría releída del IFC; datum absoluto de proceso provisional","status":"derivado"},{"label":"Cota superior de visualización","value":285.5,"unit":"m","source":"Geometría releída del IFC; datum absoluto de proceso provisional","status":"derivado"}]} | {"documentId":"LHD2609-JG00100-20260904","title":"Cimentaciones de equipos y pedestales del fabricante · revisión recibida 04/09/2026","date":"2026-09-04","sheet":"ZD1 / DZ-1","fileName":"LHD2609-JG00100_20260904.dwg","revisionCaveat":"Fecha de revisión tomada del nombre recibido; cajetines internos mantienen 02/07/2026 y algunos textos de plantilla.","sourceFileSha256":"b42eb027b7bc0b14c38d1d13514f4899b58a732aa8d0ba2ccf10fa2fc3192890"} | provisional | ["Identificador original HA-20 en columna de posición; C20 se infiere por secuencia. Se conserva el original y no se interpreta como material."] | {"Cota inferior relativa (m)":-1.0,"Cota superior relativa (m)":-0.6,"Cero absoluto de visualización (m)":286.1,"Estado del cero absoluto":"Provisional","Criterio":"Las cotas relativas proceden del dibujo; la equivalencia absoluta no está confirmada."} | {"boundingBoxM":{"min":[43.73494,53.775038,0.1],"max":[44.861825,54.901923,0.5]},"extentsM":[1.126885,1.126885,0.4],"meshSurfaceM2":3.600001,"meshVolumeM3":0.4,"closedSolid":true,"basis":"Magnitudes de las mallas representadas, no cantidades certificadas de obra, compra o fabricación. Las partes pueden compartir superficies; no se suman como un despiece de materiales."} | {"profileId":"concrete_ha30","name":"Hormigón HA-30","materialName":"Hormigón HA-30","physicalMaterialStatus":"documentado","physicalMaterialSource":"Nota general de pedestales 2CED5","appearanceStatus":"criterio_visual","appearanceBasis":"Interpretación visual del material documental; el acabado, tono y parámetros PBR no son una especificación contractual.","note":"La apariencia gráfica no modifica ni confirma la especificación física del material."} | {"elementId":"found_0904_f7b3fc3d46c563","ifcGuid":"1MwmF4M8zUqQ56oPaqmBPl","ifcClass":"IfcFooting","buildingId":"process_plant","buildingName":"Zona de separación de aire","sourceDocumentId":"LHD2609-JG00100-20260904","sourceRepresentationKind":"foundation"} | {"layerId":"foundations","layerName":"Cimentaciones","role":"Cimentación industrial","basis":"Clasificación por función del elemento; no modifica las especificaciones documentales."} | {"profileId":"concrete_ha30","name":"Hormigón HA-30","status":"criterio_visual","basis":"Interpretación visual del material documental; el acabado, tono y parámetros PBR no son una especificación contractual.","physicalMaterialUnchanged":true} | 0.4 | Hormigón HA-30 | Hormigón HA-30 | found_0904_f7b3fc3d46c563 | Nota general de pedestales 2CED5 | documentado | concrete_ha30 | [0.658824,0.658824,0.623529] | 0.94 | Zona de separación de aire; BIM · Cimentaciones | 1.12689 | 1.12688 | 0.4 | 285.1 | 285.5 | SUP-C20 | [] | ["C20"] | ZD1 / DZ-1 | ["2CCA4","2CD51","2CCC3","2CD91","2CCB3","2CCB5","2CD76","2CEB6","2CE91"] | SUP-C20/Cimentación de soporte de tuberías C20 · cuerpo de hormigón | foundation | Geometría de fabricante; implantación absoluta provisional |  | Cimentaciones de equipos y pedestales del fabricante · revisión recibida 04/09/2026 | 2CCA4, 2CD51, 2CCC3, 2CD91, 2CCB3, 2CCB5, 2CD76, 2CEB6, 2CE91 | -1 | -0.6 | 1 | Cotas relativas del dibujo. La equivalencia con un datum absoluto está pendiente. | Z del modelo = cota relativa + 1,10 m. Correspondencia provisional con 286,10 m; no es cota de obra confirmada. | Sección y contornos del fabricante; incidencias conservadas | 1 | 1 | Identificador original HA-20 en columna de posición; C20 se infiere por secuencia. Se conserva el original y no se interpreta como material. | Material: Hormigón HA-30
Cimentación de soporte de tuberías C20 · pedestal de hormigón | Parcela industrial Jinhong | Cimentación industrial | Cimentaciones de equipos y pedestales del fabricante · revisión recibida 04/09/2026 | 0.507098 | 0.507098 | 0.8 | 1.845 | 0.162 | process_plant | Zona de separación de aire | {"name":"Hormigón HA-30","status":"documentado","source":"Nota general de pedestales 2CED5"} | {"documented":[{"label":"Extensión local X","value":0.45,"unit":"m","source":"2CCA4, 2CD51, 2CCC3, 2CD91, 2CCB3, 2CCB5, 2CD76, 2CEB6, 2CE91","status":"derivada del contorno CAD"},{"label":"Extensión local Y","value":0.45,"unit":"m","source":"2CCA4, 2CD51, 2CCC3, 2CD91, 2CCB3, 2CCB5, 2CD76, 2CEB6, 2CE91","status":"derivada del contorno CAD"},{"label":"Cota inferior relativa adoptada","value":-0.6,"unit":"m","source":"ZD1 / DZ-1","status":"interpretación con conflicto conservado"},{"label":"Cota superior relativa adoptada","value":0.2,"unit":"m","source":"ZD1 / DZ-1","status":"documentada / separación por material"}],"geometry":[{"label":"Extensión de la malla en X","value":0.5070980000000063,"unit":"m","source":"Geometría releída del IFC; datum absoluto de proceso provisional","status":"derivado"},{"label":"Extensión de la malla en Y","value":0.5070979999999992,"unit":"m","source":"Geometría releída del IFC; datum absoluto de proceso provisional","status":"derivado"},{"label":"Extensión de la malla en Z","value":0.8,"unit":"m","source":"Geometría releída del IFC; datum absoluto de proceso provisional","status":"derivado"},{"label":"Cota inferior de visualización","value":285.5,"unit":"m","source":"Geometría releída del IFC; datum absoluto de proceso provisional","status":"derivado"},{"label":"Cota superior de visualización","value":286.3,"unit":"m","source":"Geometría releída del IFC; datum absoluto de proceso provisional","status":"derivado"}]} | {"documentId":"LHD2609-JG00100-20260904","title":"Cimentaciones de equipos y pedestales del fabricante · revisión recibida 04/09/2026","date":"2026-09-04","sheet":"ZD1 / DZ-1","fileName":"LHD2609-JG00100_20260904.dwg","revisionCaveat":"Fecha de revisión tomada del nombre recibido; cajetines internos mantienen 02/07/2026 y algunos textos de plantilla.","sourceFileSha256":"b42eb027b7bc0b14c38d1d13514f4899b58a732aa8d0ba2ccf10fa2fc3192890"} | provisional | ["Identificador original HA-20 en columna de posición; C20 se infiere por secuencia. Se conserva el original y no se interpreta como material."] | {"Cota inferior relativa (m)":-0.6,"Cota superior relativa (m)":0.2,"Cero absoluto de visualización (m)":286.1,"Estado del cero absoluto":"Provisional","Criterio":"Las cotas relativas proceden del dibujo; la equivalencia absoluta no está confirmada."} | {"boundingBoxM":{"min":[44.044833,54.084932,0.5],"max":[44.551931,54.59203,1.3]},"extentsM":[0.507098,0.507098,0.8],"meshSurfaceM2":1.844999,"meshVolumeM3":0.162,"closedSolid":true,"basis":"Magnitudes de las mallas representadas, no cantidades certificadas de obra, compra o fabricación. Las partes pueden compartir superficies; no se suman como un despiece de materiales."} | {"profileId":"concrete_ha30","name":"Hormigón HA-30","materialName":"Hormigón HA-30","physicalMaterialStatus":"documentado","physicalMaterialSource":"Nota general de pedestales 2CED5","appearanceStatus":"criterio_visual","appearanceBasis":"Interpretación visual del material documental; el acabado, tono y parámetros PBR no son una especificación contractual.","note":"La apariencia gráfica no modifica ni confirma la especificación física del material."} | {"elementId":"found_0904_ddc23aa7624a8e","ifcGuid":"0DorlBaY1KrOen$DQ$EF8Q","ifcClass":"IfcFooting","buildingId":"process_plant","buildingName":"Zona de separación de aire","sourceDocumentId":"LHD2609-JG00100-20260904","sourceRepresentationKind":"foundation"} | {"layerId":"foundations","layerName":"Cimentaciones","role":"Cimentación industrial","basis":"Clasificación por función del elemento; no modifica las especificaciones documentales."} | {"profileId":"concrete_ha30","name":"Hormigón HA-30","status":"criterio_visual","basis":"Interpretación visual del material documental; el acabado, tono y parámetros PBR no son una especificación contractual.","physicalMaterialUnchanged":true} | 0.162 | Hormigón HA-30 | Hormigón HA-30 | found_0904_ddc23aa7624a8e | Nota general de pedestales 2CED5 | documentado | concrete_ha30 | [0.658824,0.658824,0.623529] | 0.94 | Zona de separación de aire; BIM · Cimentaciones | 0.507098 | 0.507098 | 0.8 | 285.5 | 286.3 | SUP-C20 | [] | ["C20"] | ZD1 / DZ-1 | ["2CCA4","2CD51","2CCC3","2CD91","2CCB3","2CCB5","2CD76","2CEB6","2CE91"] | SUP-C20/Cimentación de soporte de tuberías C20 · pedestal de hormigón | foundation | Geometría de fabricante; implantación absoluta provisional |  | Cimentaciones de equipos y pedestales del fabricante · revisión recibida 04/09/2026 | 2CCA4, 2CD51, 2CCC3, 2CD91, 2CCB3, 2CCB5, 2CD76, 2CEB6, 2CE91 | -0.6 | 0.2 | 0.2025 | Cotas relativas del dibujo. La equivalencia con un datum absoluto está pendiente. | Z del modelo = cota relativa + 1,10 m. Correspondencia provisional con 286,10 m; no es cota de obra confirmada. | Sección y contornos del fabricante; incidencias conservadas | 0.45 | 0.45 | Identificador original HA-20 en columna de posición; C20 se infiere por secuencia. Se conserva el original y no se interpreta como material. | Material: Hormigón HA-30
Cimentación de soporte de tuberías C21 · cuerpo de hormigón | Parcela industrial Jinhong | Cimentación industrial | Cimentaciones de equipos y pedestales del fabricante · revisión recibida 04/09/2026 | 1.12689 | 1.12689 | 0.4 | 3.6 | 0.4 | process_plant | Zona de separación de aire | {"name":"Hormigón HA-30","status":"documentado","source":"Nota general de pedestales 2CED5"} | {"documented":[{"label":"Extensión local X","value":1.0,"unit":"m","source":"2CCA5, 2CD52, 2CCC4, 2CD92, 2CCBD, 2CCB8, 2CD77, 2CEB7, 2CE92","status":"derivada del contorno CAD"},{"label":"Extensión local Y","value":1.0,"unit":"m","source":"2CCA5, 2CD52, 2CCC4, 2CD92, 2CCBD, 2CCB8, 2CD77, 2CEB7, 2CE92","status":"derivada del contorno CAD"},{"label":"Cota inferior relativa adoptada","value":-1.0,"unit":"m","source":"ZD1 / DZ-2","status":"documentada"},{"label":"Cota superior relativa adoptada","value":-0.6,"unit":"m","source":"ZD1 / DZ-2","status":"documentada / separación por material"}],"geometry":[{"label":"Extensión de la malla en X","value":1.1268850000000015,"unit":"m","source":"Geometría releída del IFC; datum absoluto de proceso provisional","status":"derivado"},{"label":"Extensión de la malla en Y","value":1.1268850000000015,"unit":"m","source":"Geometría releída del IFC; datum absoluto de proceso provisional","status":"derivado"},{"label":"Extensión de la malla en Z","value":0.4,"unit":"m","source":"Geometría releída del IFC; datum absoluto de proceso provisional","status":"derivado"},{"label":"Cota inferior de visualización","value":285.1,"unit":"m","source":"Geometría releída del IFC; datum absoluto de proceso provisional","status":"derivado"},{"label":"Cota superior de visualización","value":285.5,"unit":"m","source":"Geometría releída del IFC; datum absoluto de proceso provisional","status":"derivado"}]} | {"documentId":"LHD2609-JG00100-20260904","title":"Cimentaciones de equipos y pedestales del fabricante · revisión recibida 04/09/2026","date":"2026-09-04","sheet":"ZD1 / DZ-2","fileName":"LHD2609-JG00100_20260904.dwg","revisionCaveat":"Fecha de revisión tomada del nombre recibido; cajetines internos mantienen 02/07/2026 y algunos textos de plantilla.","sourceFileSha256":"b42eb027b7bc0b14c38d1d13514f4899b58a732aa8d0ba2ccf10fa2fc3192890"} | provisional | [] | {"Cota inferior relativa (m)":-1.0,"Cota superior relativa (m)":-0.6,"Cero absoluto de visualización (m)":286.1,"Estado del cero absoluto":"Provisional","Criterio":"Las cotas relativas proceden del dibujo; la equivalencia absoluta no está confirmada."} | {"boundingBoxM":{"min":[51.397844,53.529028,0.1],"max":[52.524729,54.655913,0.5]},"extentsM":[1.126885,1.126885,0.4],"meshSurfaceM2":3.600001,"meshVolumeM3":0.4,"closedSolid":true,"basis":"Magnitudes de las mallas representadas, no cantidades certificadas de obra, compra o fabricación. Las partes pueden compartir superficies; no se suman como un despiece de materiales."} | {"profileId":"concrete_ha30","name":"Hormigón HA-30","materialName":"Hormigón HA-30","physicalMaterialStatus":"documentado","physicalMaterialSource":"Nota general de pedestales 2CED5","appearanceStatus":"criterio_visual","appearanceBasis":"Interpretación visual del material documental; el acabado, tono y parámetros PBR no son una especificación contractual.","note":"La apariencia gráfica no modifica ni confirma la especificación física del material."} | {"elementId":"found_0904_56768e659e77ba","ifcGuid":"28aSid3ybHRBBXHuzEpVCl","ifcClass":"IfcFooting","buildingId":"process_plant","buildingName":"Zona de separación de aire","sourceDocumentId":"LHD2609-JG00100-20260904","sourceRepresentationKind":"foundation"} | {"layerId":"foundations","layerName":"Cimentaciones","role":"Cimentación industrial","basis":"Clasificación por función del elemento; no modifica las especificaciones documentales."} | {"profileId":"concrete_ha30","name":"Hormigón HA-30","status":"criterio_visual","basis":"Interpretación visual del material documental; el acabado, tono y parámetros PBR no son una especificación contractual.","physicalMaterialUnchanged":true} | 0.4 | Hormigón HA-30 | Hormigón HA-30 | found_0904_56768e659e77ba | Nota general de pedestales 2CED5 | documentado | concrete_ha30 | [0.658824,0.658824,0.623529] | 0.94 | Zona de separación de aire; BIM · Cimentaciones | 1.12689 | 1.12689 | 0.4 | 285.1 | 285.5 | SUP-C21 | [] | ["C21"] | ZD1 / DZ-2 | ["2CCA5","2CD52","2CCC4","2CD92","2CCBD","2CCB8","2CD77","2CEB7","2CE92"] | SUP-C21/Cimentación de soporte de tuberías C21 · cuerpo de hormigón | foundation | Geometría de fabricante; implantación absoluta provisional |  | Cimentaciones de equipos y pedestales del fabricante · revisión recibida 04/09/2026 | 2CCA5, 2CD52, 2CCC4, 2CD92, 2CCBD, 2CCB8, 2CD77, 2CEB7, 2CE92 | -1 | -0.6 | 1 | Cotas relativas del dibujo. La equivalencia con un datum absoluto está pendiente. | Z del modelo = cota relativa + 1,10 m. Correspondencia provisional con 286,10 m; no es cota de obra confirmada. | Contornos y sección documentados por el fabricante | 1 | 1 | Material: Hormigón HA-30
Cimentación de soporte de tuberías C21 · pedestal de hormigón | Parcela industrial Jinhong | Cimentación industrial | Cimentaciones de equipos y pedestales del fabricante · revisión recibida 04/09/2026 | 0.563443 | 0.563443 | 0.7 | 1.9 | 0.175 | process_plant | Zona de separación de aire | {"name":"Hormigón HA-30","status":"documentado","source":"Nota general de pedestales 2CED5"} | {"documented":[{"label":"Extensión local X","value":0.5,"unit":"m","source":"2CCA5, 2CD52, 2CCC4, 2CD92, 2CCBD, 2CCB8, 2CD77, 2CEB7, 2CE92","status":"derivada del contorno CAD"},{"label":"Extensión local Y","value":0.5,"unit":"m","source":"2CCA5, 2CD52, 2CCC4, 2CD92, 2CCBD, 2CCB8, 2CD77, 2CEB7, 2CE92","status":"derivada del contorno CAD"},{"label":"Cota inferior relativa adoptada","value":-0.6,"unit":"m","source":"ZD1 / DZ-2","status":"documentada"},{"label":"Cota superior relativa adoptada","value":0.1,"unit":"m","source":"ZD1 / DZ-2","status":"documentada / separación por material"}],"geometry":[{"label":"Extensión de la malla en X","value":0.5634430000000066,"unit":"m","source":"Geometría releída del IFC; datum absoluto de proceso provisional","status":"derivado"},{"label":"Extensión de la malla en Y","value":0.5634429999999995,"unit":"m","source":"Geometría releída del IFC; datum absoluto de proceso provisional","status":"derivado"},{"label":"Extensión de la malla en Z","value":0.7,"unit":"m","source":"Geometría releída del IFC; datum absoluto de proceso provisional","status":"derivado"},{"label":"Cota inferior de visualización","value":285.5,"unit":"m","source":"Geometría releída del IFC; datum absoluto de proceso provisional","status":"derivado"},{"label":"Cota superior de visualización","value":286.2,"unit":"m","source":"Geometría releída del IFC; datum absoluto de proceso provisional","status":"derivado"}]} | {"documentId":"LHD2609-JG00100-20260904","title":"Cimentaciones de equipos y pedestales del fabricante · revisión recibida 04/09/2026","date":"2026-09-04","sheet":"ZD1 / DZ-2","fileName":"LHD2609-JG00100_20260904.dwg","revisionCaveat":"Fecha de revisión tomada del nombre recibido; cajetines internos mantienen 02/07/2026 y algunos textos de plantilla.","sourceFileSha256":"b42eb027b7bc0b14c38d1d13514f4899b58a732aa8d0ba2ccf10fa2fc3192890"} | provisional | [] | {"Cota inferior relativa (m)":-0.6,"Cota superior relativa (m)":0.1,"Cero absoluto de visualización (m)":286.1,"Estado del cero absoluto":"Provisional","Criterio":"Las cotas relativas proceden del dibujo; la equivalencia absoluta no está confirmada."} | {"boundingBoxM":{"min":[51.679565,53.810749,0.5],"max":[52.243008,54.374192,1.2]},"extentsM":[0.563443,0.563443,0.7],"meshSurfaceM2":1.900003,"meshVolumeM3":0.175,"closedSolid":true,"basis":"Magnitudes de las mallas representadas, no cantidades certificadas de obra, compra o fabricación. Las partes pueden compartir superficies; no se suman como un despiece de materiales."} | {"profileId":"concrete_ha30","name":"Hormigón HA-30","materialName":"Hormigón HA-30","physicalMaterialStatus":"documentado","physicalMaterialSource":"Nota general de pedestales 2CED5","appearanceStatus":"criterio_visual","appearanceBasis":"Interpretación visual del material documental; el acabado, tono y parámetros PBR no son una especificación contractual.","note":"La apariencia gráfica no modifica ni confirma la especificación física del material."} | {"elementId":"found_0904_e8dbb58287e2aa","ifcGuid":"0SoPwUfS1KX8G$piVrpBrm","ifcClass":"IfcFooting","buildingId":"process_plant","buildingName":"Zona de separación de aire","sourceDocumentId":"LHD2609-JG00100-20260904","sourceRepresentationKind":"foundation"} | {"layerId":"foundations","layerName":"Cimentaciones","role":"Cimentación industrial","basis":"Clasificación por función del elemento; no modifica las especificaciones documentales."} | {"profileId":"concrete_ha30","name":"Hormigón HA-30","status":"criterio_visual","basis":"Interpretación visual del material documental; el acabado, tono y parámetros PBR no son una especificación contractual.","physicalMaterialUnchanged":true} | 0.175 | Hormigón HA-30 | Hormigón HA-30 | found_0904_e8dbb58287e2aa | Nota general de pedestales 2CED5 | documentado | concrete_ha30 | [0.658824,0.658824,0.623529] | 0.94 | Zona de separación de aire; BIM · Cimentaciones | 0.563443 | 0.563443 | 0.7 | 285.5 | 286.2 | SUP-C21 | [] | ["C21"] | ZD1 / DZ-2 | ["2CCA5","2CD52","2CCC4","2CD92","2CCBD","2CCB8","2CD77","2CEB7","2CE92"] | SUP-C21/Cimentación de soporte de tuberías C21 · pedestal de hormigón | foundation | Geometría de fabricante; implantación absoluta provisional |  | Cimentaciones de equipos y pedestales del fabricante · revisión recibida 04/09/2026 | 2CCA5, 2CD52, 2CCC4, 2CD92, 2CCBD, 2CCB8, 2CD77, 2CEB7, 2CE92 | -0.6 | 0.1 | 0.25 | Cotas relativas del dibujo. La equivalencia con un datum absoluto está pendiente. | Z del modelo = cota relativa + 1,10 m. Correspondencia provisional con 286,10 m; no es cota de obra confirmada. | Contornos y sección documentados por el fabricante | 0.5 | 0.5 | Material: Hormigón HA-30
Cimentación de soporte de tuberías C22 · cuerpo de hormigón | Parcela industrial Jinhong | Cimentación industrial | Cimentaciones de equipos y pedestales del fabricante · revisión recibida 04/09/2026 | 1.12689 | 1.12688 | 0.4 | 3.6 | 0.4 | process_plant | Zona de separación de aire | {"name":"Hormigón HA-30","status":"documentado","source":"Nota general de pedestales 2CED5"} | {"documented":[{"label":"Extensión local X","value":1.0,"unit":"m","source":"2CCA6, 2CD53, 2CCC5, 2CD93, 2CCBB, 2CCBC, 2CD82, 2CEB8, 2CE93","status":"derivada del contorno CAD"},{"label":"Extensión local Y","value":1.0,"unit":"m","source":"2CCA6, 2CD53, 2CCC5, 2CD93, 2CCBB, 2CCBC, 2CD82, 2CEB8, 2CE93","status":"derivada del contorno CAD"},{"label":"Cota inferior relativa adoptada","value":-1.0,"unit":"m","source":"ZD1 / DZ-2","status":"documentada"},{"label":"Cota superior relativa adoptada","value":-0.6,"unit":"m","source":"ZD1 / DZ-2","status":"documentada / separación por material"}],"geometry":[{"label":"Extensión de la malla en X","value":1.1268850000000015,"unit":"m","source":"Geometría releída del IFC; datum absoluto de proceso provisional","status":"derivado"},{"label":"Extensión de la malla en Y","value":1.126884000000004,"unit":"m","source":"Geometría releída del IFC; datum absoluto de proceso provisional","status":"derivado"},{"label":"Extensión de la malla en Z","value":0.4,"unit":"m","source":"Geometría releída del IFC; datum absoluto de proceso provisional","status":"derivado"},{"label":"Cota inferior de visualización","value":285.1,"unit":"m","source":"Geometría releída del IFC; datum absoluto de proceso provisional","status":"derivado"},{"label":"Cota superior de visualización","value":285.5,"unit":"m","source":"Geometría releída del IFC; datum absoluto de proceso provisional","status":"derivado"}]} | {"documentId":"LHD2609-JG00100-20260904","title":"Cimentaciones de equipos y pedestales del fabricante · revisión recibida 04/09/2026","date":"2026-09-04","sheet":"ZD1 / DZ-2","fileName":"LHD2609-JG00100_20260904.dwg","revisionCaveat":"Fecha de revisión tomada del nombre recibido; cajetines internos mantienen 02/07/2026 y algunos textos de plantilla.","sourceFileSha256":"b42eb027b7bc0b14c38d1d13514f4899b58a732aa8d0ba2ccf10fa2fc3192890"} | provisional | [] | {"Cota inferior relativa (m)":-1.0,"Cota superior relativa (m)":-0.6,"Cero absoluto de visualización (m)":286.1,"Estado del cero absoluto":"Provisional","Criterio":"Las cotas relativas proceden del dibujo; la equivalencia absoluta no está confirmada."} | {"boundingBoxM":{"min":[54.023148,53.168088,0.1],"max":[55.150033,54.294972,0.5]},"extentsM":[1.126885,1.126884,0.4],"meshSurfaceM2":3.599999,"meshVolumeM3":0.4,"closedSolid":true,"basis":"Magnitudes de las mallas representadas, no cantidades certificadas de obra, compra o fabricación. Las partes pueden compartir superficies; no se suman como un despiece de materiales."} | {"profileId":"concrete_ha30","name":"Hormigón HA-30","materialName":"Hormigón HA-30","physicalMaterialStatus":"documentado","physicalMaterialSource":"Nota general de pedestales 2CED5","appearanceStatus":"criterio_visual","appearanceBasis":"Interpretación visual del material documental; el acabado, tono y parámetros PBR no son una especificación contractual.","note":"La apariencia gráfica no modifica ni confirma la especificación física del material."} | {"elementId":"found_0904_7b0e626d214cfb","ifcGuid":"1vdze23hbSMhriBkZFJwyA","ifcClass":"IfcFooting","buildingId":"process_plant","buildingName":"Zona de separación de aire","sourceDocumentId":"LHD2609-JG00100-20260904","sourceRepresentationKind":"foundation"} | {"layerId":"foundations","layerName":"Cimentaciones","role":"Cimentación industrial","basis":"Clasificación por función del elemento; no modifica las especificaciones documentales."} | {"profileId":"concrete_ha30","name":"Hormigón HA-30","status":"criterio_visual","basis":"Interpretación visual del material documental; el acabado, tono y parámetros PBR no son una especificación contractual.","physicalMaterialUnchanged":true} | 0.4 | Hormigón HA-30 | Hormigón HA-30 | found_0904_7b0e626d214cfb | Nota general de pedestales 2CED5 | documentado | concrete_ha30 | [0.658824,0.658824,0.623529] | 0.94 | Zona de separación de aire; BIM · Cimentaciones | 1.12689 | 1.12688 | 0.4 | 285.1 | 285.5 | SUP-C22 | [] | ["C22"] | ZD1 / DZ-2 | ["2CCA6","2CD53","2CCC5","2CD93","2CCBB","2CCBC","2CD82","2CEB8","2CE93"] | SUP-C22/Cimentación de soporte de tuberías C22 · cuerpo de hormigón | foundation | Geometría de fabricante; implantación absoluta provisional |  | Cimentaciones de equipos y pedestales del fabricante · revisión recibida 04/09/2026 | 2CCA6, 2CD53, 2CCC5, 2CD93, 2CCBB, 2CCBC, 2CD82, 2CEB8, 2CE93 | -1 | -0.6 | 1 | Cotas relativas del dibujo. La equivalencia con un datum absoluto está pendiente. | Z del modelo = cota relativa + 1,10 m. Correspondencia provisional con 286,10 m; no es cota de obra confirmada. | Contornos y sección documentados por el fabricante | 1 | 1 | Material: Hormigón HA-30
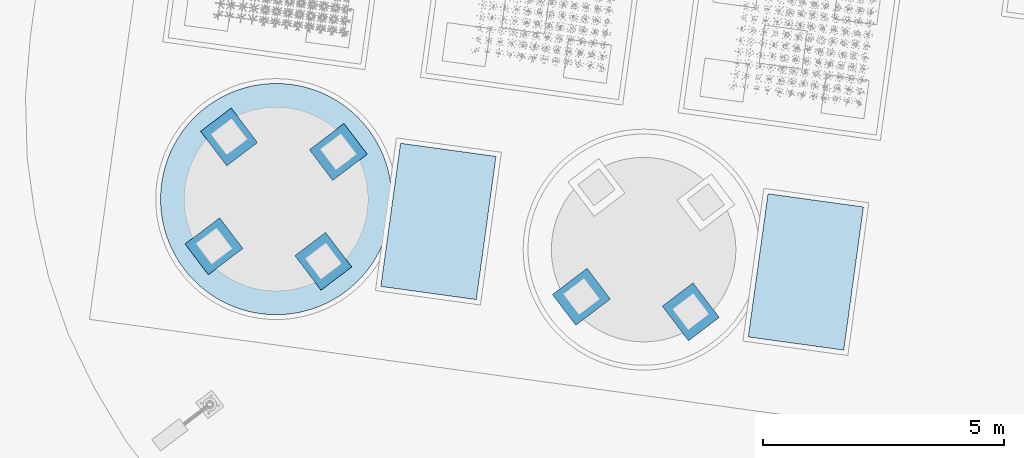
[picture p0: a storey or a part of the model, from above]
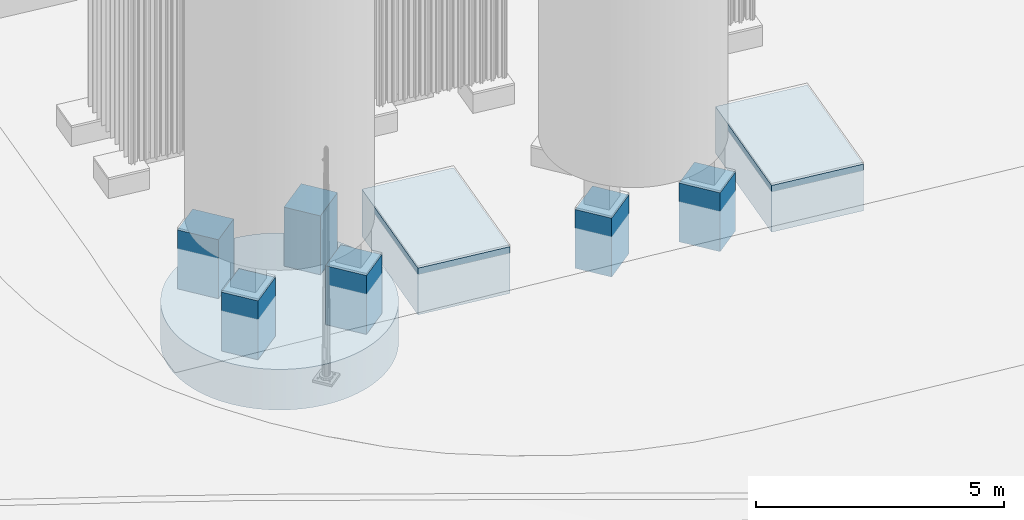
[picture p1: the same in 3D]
Properties of the parts of a building model (IFC4), part 82 of 134

# IfcFooting (214)
Name | In | Description = category = Categoria = Funcion | Document | ExtensionX (m) | ExtensionY (m) | ExtensionZ (m) | SuperficieDeLaMalla (m2) | VolumenGeometrico (m3) | buildingId | buildingName | material | dimensions | JH_InformacionBIM, source = DocumentoFuente | JH_InformacionBIM, status = EstadoDeInformacion | issues = IncidenciasPendientes | positioning = PosicionYEstado | geometryMetrics | materialAppearance | visualizationIdentity | classification | appearance | Volumen geométrico (m³) | JH_Trazabilidad, Material = name | Acabado de visualización = Acabado | Identificador | JH_EvidenciaDeMaterial, source | JH_EvidenciaDeMaterial, status | Perfil | ColorRGB | Rugosidad | Group | Extensión de la malla en X (m) | Extensión de la malla en Y (m) | Extensión de la malla en Z (m) = Espesor o altura real de sección (m) | Cota inferior de visualización (m) | Cota superior de visualización (m) | assemblyId = Conjunto de cimentación | equipmentIds | supportPositionIds | sectionRef = Sección de referencia | sourceCadHandles | stableElementKey | representationKind | geometryStatus | Equipos asociados | Documento de origen | Identificadores CAD de referencia | Cota inferior relativa (m) = Cota inferior relativa adoptada (m) | Cota superior relativa (m) = Cota superior relativa adoptada (m) | Área de planta (m²) | Referencia vertical | Implantación para visualización | Estado de la geometría | Extensión local X (m) | Extensión local Y (m) | Incidencias de origen
Cimentación de soporte de tuberías C22 · pedestal de hormigón | Parcela industrial Jinhong | Cimentación industrial | Cimentaciones de equipos y pedestales del fabricante · revisión recibida 04/09/2026 | 0.563442 | 0.563442 | 0.7 | 1.9 | 0.175 | process_plant | Zona de separación de aire | {"name":"Hormigón HA-30","status":"documentado","source":"Nota general de pedestales 2CED5"} | {"documented":[{"label":"Extensión local X","value":0.5,"unit":"m","source":"2CCA6, 2CD53, 2CCC5, 2CD93, 2CCBB, 2CCBC, 2CD82, 2CEB8, 2CE93","status":"derivada del contorno CAD"},{"label":"Extensión local Y","value":0.5,"unit":"m","source":"2CCA6, 2CD53, 2CCC5, 2CD93, 2CCBB, 2CCBC, 2CD82, 2CEB8, 2CE93","status":"derivada del contorno CAD"},{"label":"Cota inferior relativa adoptada","value":-0.6,"unit":"m","source":"ZD1 / DZ-2","status":"documentada"},{"label":"Cota superior relativa adoptada","value":0.1,"unit":"m","source":"ZD1 / DZ-2","status":"documentada / separación por material"}],"geometry":[{"label":"Extensión de la malla en X","value":0.563442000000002,"unit":"m","source":"Geometría releída del IFC; datum absoluto de proceso provisional","status":"derivado"},{"label":"Extensión de la malla en Y","value":0.5634419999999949,"unit":"m","source":"Geometría releída del IFC; datum absoluto de proceso provisional","status":"derivado"},{"label":"Extensión de la malla en Z","value":0.7,"unit":"m","source":"Geometría releída del IFC; datum absoluto de proceso provisional","status":"derivado"},{"label":"Cota inferior de visualización","value":285.5,"unit":"m","source":"Geometría releída del IFC; datum absoluto de proceso provisional","status":"derivado"},{"label":"Cota superior de visualización","value":286.2,"unit":"m","source":"Geometría releída del IFC; datum absoluto de proceso provisional","status":"derivado"}]} | {"documentId":"LHD2609-JG00100-20260904","title":"Cimentaciones de equipos y pedestales del fabricante · revisión recibida 04/09/2026","date":"2026-09-04","sheet":"ZD1 / DZ-2","fileName":"LHD2609-JG00100_20260904.dwg","revisionCaveat":"Fecha de revisión tomada del nombre recibido; cajetines internos mantienen 02/07/2026 y algunos textos de plantilla.","sourceFileSha256":"b42eb027b7bc0b14c38d1d13514f4899b58a732aa8d0ba2ccf10fa2fc3192890"} | provisional | [] | {"Cota inferior relativa (m)":-0.6,"Cota superior relativa (m)":0.1,"Cero absoluto de visualización (m)":286.1,"Estado del cero absoluto":"Provisional","Criterio":"Las cotas relativas proceden del dibujo; la equivalencia absoluta no está confirmada."} | {"boundingBoxM":{"min":[54.30487,53.449809,0.5],"max":[54.868312,54.013251,1.2]},"extentsM":[0.563442,0.563442,0.7],"meshSurfaceM2":1.899999,"meshVolumeM3":0.175,"closedSolid":true,"basis":"Magnitudes de las mallas representadas, no cantidades certificadas de obra, compra o fabricación. Las partes pueden compartir superficies; no se suman como un despiece de materiales."} | {"profileId":"concrete_ha30","name":"Hormigón HA-30","materialName":"Hormigón HA-30","physicalMaterialStatus":"documentado","physicalMaterialSource":"Nota general de pedestales 2CED5","appearanceStatus":"criterio_visual","appearanceBasis":"Interpretación visual del material documental; el acabado, tono y parámetros PBR no son una especificación contractual.","note":"La apariencia gráfica no modifica ni confirma la especificación física del material."} | {"elementId":"found_0904_d29f723f769bdf","ifcGuid":"1QwZ9zhYzSox$gz1kv6ls0","ifcClass":"IfcFooting","buildingId":"process_plant","buildingName":"Zona de separación de aire","sourceDocumentId":"LHD2609-JG00100-20260904","sourceRepresentationKind":"foundation"} | {"layerId":"foundations","layerName":"Cimentaciones","role":"Cimentación industrial","basis":"Clasificación por función del elemento; no modifica las especificaciones documentales."} | {"profileId":"concrete_ha30","name":"Hormigón HA-30","status":"criterio_visual","basis":"Interpretación visual del material documental; el acabado, tono y parámetros PBR no son una especificación contractual.","physicalMaterialUnchanged":true} | 0.175 | Hormigón HA-30 | Hormigón HA-30 | found_0904_d29f723f769bdf | Nota general de pedestales 2CED5 | documentado | concrete_ha30 | [0.658824,0.658824,0.623529] | 0.94 | Zona de separación de aire; BIM · Cimentaciones | 0.563442 | 0.563442 | 0.7 | 285.5 | 286.2 | SUP-C22 | [] | ["C22"] | ZD1 / DZ-2 | ["2CCA6","2CD53","2CCC5","2CD93","2CCBB","2CCBC","2CD82","2CEB8","2CE93"] | SUP-C22/Cimentación de soporte de tuberías C22 · pedestal de hormigón | foundation | Geometría de fabricante; implantación absoluta provisional |  | Cimentaciones de equipos y pedestales del fabricante · revisión recibida 04/09/2026 | 2CCA6, 2CD53, 2CCC5, 2CD93, 2CCBB, 2CCBC, 2CD82, 2CEB8, 2CE93 | -0.6 | 0.1 | 0.25 | Cotas relativas del dibujo. La equivalencia con un datum absoluto está pendiente. | Z del modelo = cota relativa + 1,10 m. Correspondencia provisional con 286,10 m; no es cota de obra confirmada. | Contornos y sección documentados por el fabricante | 0.5 | 0.5 | Material: Hormigón HA-30
Cimentación de soporte de tuberías C23 · cuerpo de hormigón | Parcela industrial Jinhong | Cimentación industrial | Cimentaciones de equipos y pedestales del fabricante · revisión recibida 04/09/2026 | 1.12688 | 1.12689 | 0.4 | 3.6 | 0.4 | process_plant | Zona de separación de aire | {"name":"Hormigón HA-30","status":"documentado","source":"Nota general de pedestales 2CED5"} | {"documented":[{"label":"Extensión local X","value":1.0,"unit":"m","source":"2CCA7, 2CD5F, 2CCC6, 2CD94, 2CCB9, 2CCBA, 2CD83, 2CEB9, 2CE94","status":"derivada del contorno CAD"},{"label":"Extensión local Y","value":1.0,"unit":"m","source":"2CCA7, 2CD5F, 2CCC6, 2CD94, 2CCB9, 2CCBA, 2CD83, 2CEB9, 2CE94","status":"derivada del contorno CAD"},{"label":"Cota inferior relativa adoptada","value":-1.0,"unit":"m","source":"ZD1 / DZ-2","status":"documentada"},{"label":"Cota superior relativa adoptada","value":-0.6,"unit":"m","source":"ZD1 / DZ-2","status":"documentada / separación por material"}],"geometry":[{"label":"Extensión de la malla en X","value":1.1268849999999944,"unit":"m","source":"Geometría releída del IFC; datum absoluto de proceso provisional","status":"derivado"},{"label":"Extensión de la malla en Y","value":1.1268850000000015,"unit":"m","source":"Geometría releída del IFC; datum absoluto de proceso provisional","status":"derivado"},{"label":"Extensión de la malla en Z","value":0.4,"unit":"m","source":"Geometría releída del IFC; datum absoluto de proceso provisional","status":"derivado"},{"label":"Cota inferior de visualización","value":285.1,"unit":"m","source":"Geometría releída del IFC; datum absoluto de proceso provisional","status":"derivado"},{"label":"Cota superior de visualización","value":285.5,"unit":"m","source":"Geometría releída del IFC; datum absoluto de proceso provisional","status":"derivado"}]} | {"documentId":"LHD2609-JG00100-20260904","title":"Cimentaciones de equipos y pedestales del fabricante · revisión recibida 04/09/2026","date":"2026-09-04","sheet":"ZD1 / DZ-2","fileName":"LHD2609-JG00100_20260904.dwg","revisionCaveat":"Fecha de revisión tomada del nombre recibido; cajetines internos mantienen 02/07/2026 y algunos textos de plantilla.","sourceFileSha256":"b42eb027b7bc0b14c38d1d13514f4899b58a732aa8d0ba2ccf10fa2fc3192890"} | provisional | [] | {"Cota inferior relativa (m)":-1.0,"Cota superior relativa (m)":-0.6,"Cero absoluto de visualización (m)":286.1,"Estado del cero absoluto":"Provisional","Criterio":"Las cotas relativas proceden del dibujo; la equivalencia absoluta no está confirmada."} | {"boundingBoxM":{"min":[56.33268,52.345858,0.1],"max":[57.459565,53.472743,0.5]},"extentsM":[1.126885,1.126885,0.4],"meshSurfaceM2":3.600001,"meshVolumeM3":0.4,"closedSolid":true,"basis":"Magnitudes de las mallas representadas, no cantidades certificadas de obra, compra o fabricación. Las partes pueden compartir superficies; no se suman como un despiece de materiales."} | {"profileId":"concrete_ha30","name":"Hormigón HA-30","materialName":"Hormigón HA-30","physicalMaterialStatus":"documentado","physicalMaterialSource":"Nota general de pedestales 2CED5","appearanceStatus":"criterio_visual","appearanceBasis":"Interpretación visual del material documental; el acabado, tono y parámetros PBR no son una especificación contractual.","note":"La apariencia gráfica no modifica ni confirma la especificación física del material."} | {"elementId":"found_0904_66c54939739283","ifcGuid":"14i7U424TPZRJPmHKxHii6","ifcClass":"IfcFooting","buildingId":"process_plant","buildingName":"Zona de separación de aire","sourceDocumentId":"LHD2609-JG00100-20260904","sourceRepresentationKind":"foundation"} | {"layerId":"foundations","layerName":"Cimentaciones","role":"Cimentación industrial","basis":"Clasificación por función del elemento; no modifica las especificaciones documentales."} | {"profileId":"concrete_ha30","name":"Hormigón HA-30","status":"criterio_visual","basis":"Interpretación visual del material documental; el acabado, tono y parámetros PBR no son una especificación contractual.","physicalMaterialUnchanged":true} | 0.4 | Hormigón HA-30 | Hormigón HA-30 | found_0904_66c54939739283 | Nota general de pedestales 2CED5 | documentado | concrete_ha30 | [0.658824,0.658824,0.623529] | 0.94 | Zona de separación de aire; BIM · Cimentaciones | 1.12688 | 1.12689 | 0.4 | 285.1 | 285.5 | SUP-C23 | [] | ["C23"] | ZD1 / DZ-2 | ["2CCA7","2CD5F","2CCC6","2CD94","2CCB9","2CCBA","2CD83","2CEB9","2CE94"] | SUP-C23/Cimentación de soporte de tuberías C23 · cuerpo de hormigón | foundation | Geometría de fabricante; implantación absoluta provisional |  | Cimentaciones de equipos y pedestales del fabricante · revisión recibida 04/09/2026 | 2CCA7, 2CD5F, 2CCC6, 2CD94, 2CCB9, 2CCBA, 2CD83, 2CEB9, 2CE94 | -1 | -0.6 | 1 | Cotas relativas del dibujo. La equivalencia con un datum absoluto está pendiente. | Z del modelo = cota relativa + 1,10 m. Correspondencia provisional con 286,10 m; no es cota de obra confirmada. | Contornos y sección documentados por el fabricante | 1 | 1 | Material: Hormigón HA-30
Cimentación de soporte de tuberías C23 · pedestal de hormigón | Parcela industrial Jinhong | Cimentación industrial | Cimentaciones de equipos y pedestales del fabricante · revisión recibida 04/09/2026 | 0.563442 | 0.563442 | 0.8 | 2.1 | 0.2 | process_plant | Zona de separación de aire | {"name":"Hormigón HA-30","status":"documentado","source":"Nota general de pedestales 2CED5"} | {"documented":[{"label":"Extensión local X","value":0.5,"unit":"m","source":"2CCA7, 2CD5F, 2CCC6, 2CD94, 2CCB9, 2CCBA, 2CD83, 2CEB9, 2CE94","status":"derivada del contorno CAD"},{"label":"Extensión local Y","value":0.5,"unit":"m","source":"2CCA7, 2CD5F, 2CCC6, 2CD94, 2CCB9, 2CCBA, 2CD83, 2CEB9, 2CE94","status":"derivada del contorno CAD"},{"label":"Cota inferior relativa adoptada","value":-0.6,"unit":"m","source":"ZD1 / DZ-2","status":"documentada"},{"label":"Cota superior relativa adoptada","value":0.2,"unit":"m","source":"ZD1 / DZ-2","status":"documentada / separación por material"}],"geometry":[{"label":"Extensión de la malla en X","value":0.563442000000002,"unit":"m","source":"Geometría releída del IFC; datum absoluto de proceso provisional","status":"derivado"},{"label":"Extensión de la malla en Y","value":0.563442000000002,"unit":"m","source":"Geometría releída del IFC; datum absoluto de proceso provisional","status":"derivado"},{"label":"Extensión de la malla en Z","value":0.8,"unit":"m","source":"Geometría releída del IFC; datum absoluto de proceso provisional","status":"derivado"},{"label":"Cota inferior de visualización","value":285.5,"unit":"m","source":"Geometría releída del IFC; datum absoluto de proceso provisional","status":"derivado"},{"label":"Cota superior de visualización","value":286.3,"unit":"m","source":"Geometría releída del IFC; datum absoluto de proceso provisional","status":"derivado"}]} | {"documentId":"LHD2609-JG00100-20260904","title":"Cimentaciones de equipos y pedestales del fabricante · revisión recibida 04/09/2026","date":"2026-09-04","sheet":"ZD1 / DZ-2","fileName":"LHD2609-JG00100_20260904.dwg","revisionCaveat":"Fecha de revisión tomada del nombre recibido; cajetines internos mantienen 02/07/2026 y algunos textos de plantilla.","sourceFileSha256":"b42eb027b7bc0b14c38d1d13514f4899b58a732aa8d0ba2ccf10fa2fc3192890"} | provisional | [] | {"Cota inferior relativa (m)":-0.6,"Cota superior relativa (m)":0.2,"Cero absoluto de visualización (m)":286.1,"Estado del cero absoluto":"Provisional","Criterio":"Las cotas relativas proceden del dibujo; la equivalencia absoluta no está confirmada."} | {"boundingBoxM":{"min":[56.614402,52.627579,0.5],"max":[57.177844,53.191021,1.3]},"extentsM":[0.563442,0.563442,0.8],"meshSurfaceM2":2.1,"meshVolumeM3":0.2,"closedSolid":true,"basis":"Magnitudes de las mallas representadas, no cantidades certificadas de obra, compra o fabricación. Las partes pueden compartir superficies; no se suman como un despiece de materiales."} | {"profileId":"concrete_ha30","name":"Hormigón HA-30","materialName":"Hormigón HA-30","physicalMaterialStatus":"documentado","physicalMaterialSource":"Nota general de pedestales 2CED5","appearanceStatus":"criterio_visual","appearanceBasis":"Interpretación visual del material documental; el acabado, tono y parámetros PBR no son una especificación contractual.","note":"La apariencia gráfica no modifica ni confirma la especificación física del material."} | {"elementId":"found_0904_c9d940e21ac0d8","ifcGuid":"3JFT1_9ZHSfgJGDkEhURW6","ifcClass":"IfcFooting","buildingId":"process_plant","buildingName":"Zona de separación de aire","sourceDocumentId":"LHD2609-JG00100-20260904","sourceRepresentationKind":"foundation"} | {"layerId":"foundations","layerName":"Cimentaciones","role":"Cimentación industrial","basis":"Clasificación por función del elemento; no modifica las especificaciones documentales."} | {"profileId":"concrete_ha30","name":"Hormigón HA-30","status":"criterio_visual","basis":"Interpretación visual del material documental; el acabado, tono y parámetros PBR no son una especificación contractual.","physicalMaterialUnchanged":true} | 0.2 | Hormigón HA-30 | Hormigón HA-30 | found_0904_c9d940e21ac0d8 | Nota general de pedestales 2CED5 | documentado | concrete_ha30 | [0.658824,0.658824,0.623529] | 0.94 | Zona de separación de aire; BIM · Cimentaciones | 0.563442 | 0.563442 | 0.8 | 285.5 | 286.3 | SUP-C23 | [] | ["C23"] | ZD1 / DZ-2 | ["2CCA7","2CD5F","2CCC6","2CD94","2CCB9","2CCBA","2CD83","2CEB9","2CE94"] | SUP-C23/Cimentación de soporte de tuberías C23 · pedestal de hormigón | foundation | Geometría de fabricante; implantación absoluta provisional |  | Cimentaciones de equipos y pedestales del fabricante · revisión recibida 04/09/2026 | 2CCA7, 2CD5F, 2CCC6, 2CD94, 2CCB9, 2CCBA, 2CD83, 2CEB9, 2CE94 | -0.6 | 0.2 | 0.25 | Cotas relativas del dibujo. La equivalencia con un datum absoluto está pendiente. | Z del modelo = cota relativa + 1,10 m. Correspondencia provisional con 286,10 m; no es cota de obra confirmada. | Contornos y sección documentados por el fabricante | 0.5 | 0.5 | Material: Hormigón HA-30
Cimentación de soporte de tuberías C24 · cuerpo de hormigón | Parcela industrial Jinhong | Cimentación industrial | Cimentaciones de equipos y pedestales del fabricante · revisión recibida 04/09/2026 | 1.12689 | 1.12688 | 0.4 | 3.6 | 0.4 | process_plant | Zona de separación de aire | {"name":"Hormigón HA-30","status":"documentado","source":"Nota general de pedestales 2CED5"} | {"documented":[{"label":"Extensión local X","value":1.0,"unit":"m","source":"2CCA8, 2CD60, 2CCC7, 2CD95, 2CCB6, 2CCB7, 2CD84, 2CEBA, 2CE95","status":"derivada del contorno CAD"},{"label":"Extensión local Y","value":1.0,"unit":"m","source":"2CCA8, 2CD60, 2CCC7, 2CD95, 2CCB6, 2CCB7, 2CD84, 2CEBA, 2CE95","status":"derivada del contorno CAD"},{"label":"Cota inferior relativa adoptada","value":-1.0,"unit":"m","source":"ZD1 / DZ-2","status":"documentada"},{"label":"Cota superior relativa adoptada","value":-0.6,"unit":"m","source":"ZD1 / DZ-2","status":"documentada / separación por material"}],"geometry":[{"label":"Extensión de la malla en X","value":1.1268850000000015,"unit":"m","source":"Geometría releída del IFC; datum absoluto de proceso provisional","status":"derivado"},{"label":"Extensión de la malla en Y","value":1.126884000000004,"unit":"m","source":"Geometría releída del IFC; datum absoluto de proceso provisional","status":"derivado"},{"label":"Extensión de la malla en Z","value":0.4,"unit":"m","source":"Geometría releída del IFC; datum absoluto de proceso provisional","status":"derivado"},{"label":"Cota inferior de visualización","value":285.1,"unit":"m","source":"Geometría releída del IFC; datum absoluto de proceso provisional","status":"derivado"},{"label":"Cota superior de visualización","value":285.5,"unit":"m","source":"Geometría releída del IFC; datum absoluto de proceso provisional","status":"derivado"}]} | {"documentId":"LHD2609-JG00100-20260904","title":"Cimentaciones de equipos y pedestales del fabricante · revisión recibida 04/09/2026","date":"2026-09-04","sheet":"ZD1 / DZ-2","fileName":"LHD2609-JG00100_20260904.dwg","revisionCaveat":"Fecha de revisión tomada del nombre recibido; cajetines internos mantienen 02/07/2026 y algunos textos de plantilla.","sourceFileSha256":"b42eb027b7bc0b14c38d1d13514f4899b58a732aa8d0ba2ccf10fa2fc3192890"} | provisional | [] | {"Cota inferior relativa (m)":-1.0,"Cota superior relativa (m)":-0.6,"Cero absoluto de visualización (m)":286.1,"Estado del cero absoluto":"Provisional","Criterio":"Las cotas relativas proceden del dibujo; la equivalencia absoluta no está confirmada."} | {"boundingBoxM":{"min":[56.128374,50.859837,0.1],"max":[57.255259,51.986721,0.5]},"extentsM":[1.126885,1.126884,0.4],"meshSurfaceM2":3.599999,"meshVolumeM3":0.4,"closedSolid":true,"basis":"Magnitudes de las mallas representadas, no cantidades certificadas de obra, compra o fabricación. Las partes pueden compartir superficies; no se suman como un despiece de materiales."} | {"profileId":"concrete_ha30","name":"Hormigón HA-30","materialName":"Hormigón HA-30","physicalMaterialStatus":"documentado","physicalMaterialSource":"Nota general de pedestales 2CED5","appearanceStatus":"criterio_visual","appearanceBasis":"Interpretación visual del material documental; el acabado, tono y parámetros PBR no son una especificación contractual.","note":"La apariencia gráfica no modifica ni confirma la especificación física del material."} | {"elementId":"found_0904_2331cde6020269","ifcGuid":"2Fnx4sBj5N1hA_iu7G8VtG","ifcClass":"IfcFooting","buildingId":"process_plant","buildingName":"Zona de separación de aire","sourceDocumentId":"LHD2609-JG00100-20260904","sourceRepresentationKind":"foundation"} | {"layerId":"foundations","layerName":"Cimentaciones","role":"Cimentación industrial","basis":"Clasificación por función del elemento; no modifica las especificaciones documentales."} | {"profileId":"concrete_ha30","name":"Hormigón HA-30","status":"criterio_visual","basis":"Interpretación visual del material documental; el acabado, tono y parámetros PBR no son una especificación contractual.","physicalMaterialUnchanged":true} | 0.4 | Hormigón HA-30 | Hormigón HA-30 | found_0904_2331cde6020269 | Nota general de pedestales 2CED5 | documentado | concrete_ha30 | [0.658824,0.658824,0.623529] | 0.94 | Zona de separación de aire; BIM · Cimentaciones | 1.12689 | 1.12688 | 0.4 | 285.1 | 285.5 | SUP-C24 | [] | ["C24"] | ZD1 / DZ-2 | ["2CCA8","2CD60","2CCC7","2CD95","2CCB6","2CCB7","2CD84","2CEBA","2CE95"] | SUP-C24/Cimentación de soporte de tuberías C24 · cuerpo de hormigón | foundation | Geometría de fabricante; implantación absoluta provisional |  | Cimentaciones de equipos y pedestales del fabricante · revisión recibida 04/09/2026 | 2CCA8, 2CD60, 2CCC7, 2CD95, 2CCB6, 2CCB7, 2CD84, 2CEBA, 2CE95 | -1 | -0.6 | 1 | Cotas relativas del dibujo. La equivalencia con un datum absoluto está pendiente. | Z del modelo = cota relativa + 1,10 m. Correspondencia provisional con 286,10 m; no es cota de obra confirmada. | Contornos y sección documentados por el fabricante | 1 | 1 | Material: Hormigón HA-30
Cimentación de soporte de tuberías C24 · pedestal de hormigón | Parcela industrial Jinhong | Cimentación industrial | Cimentaciones de equipos y pedestales del fabricante · revisión recibida 04/09/2026 | 0.563442 | 0.563442 | 0.8 | 2.1 | 0.2 | process_plant | Zona de separación de aire | {"name":"Hormigón HA-30","status":"documentado","source":"Nota general de pedestales 2CED5"} | {"documented":[{"label":"Extensión local X","value":0.5,"unit":"m","source":"2CCA8, 2CD60, 2CCC7, 2CD95, 2CCB6, 2CCB7, 2CD84, 2CEBA, 2CE95","status":"derivada del contorno CAD"},{"label":"Extensión local Y","value":0.5,"unit":"m","source":"2CCA8, 2CD60, 2CCC7, 2CD95, 2CCB6, 2CCB7, 2CD84, 2CEBA, 2CE95","status":"derivada del contorno CAD"},{"label":"Cota inferior relativa adoptada","value":-0.6,"unit":"m","source":"ZD1 / DZ-2","status":"documentada"},{"label":"Cota superior relativa adoptada","value":0.2,"unit":"m","source":"ZD1 / DZ-2","status":"documentada / separación por material"}],"geometry":[{"label":"Extensión de la malla en X","value":0.5634419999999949,"unit":"m","source":"Geometría releída del IFC; datum absoluto de proceso provisional","status":"derivado"},{"label":"Extensión de la malla en Y","value":0.5634419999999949,"unit":"m","source":"Geometría releída del IFC; datum absoluto de proceso provisional","status":"derivado"},{"label":"Extensión de la malla en Z","value":0.8,"unit":"m","source":"Geometría releída del IFC; datum absoluto de proceso provisional","status":"derivado"},{"label":"Cota inferior de visualización","value":285.5,"unit":"m","source":"Geometría releída del IFC; datum absoluto de proceso provisional","status":"derivado"},{"label":"Cota superior de visualización","value":286.3,"unit":"m","source":"Geometría releída del IFC; datum absoluto de proceso provisional","status":"derivado"}]} | {"documentId":"LHD2609-JG00100-20260904","title":"Cimentaciones de equipos y pedestales del fabricante · revisión recibida 04/09/2026","date":"2026-09-04","sheet":"ZD1 / DZ-2","fileName":"LHD2609-JG00100_20260904.dwg","revisionCaveat":"Fecha de revisión tomada del nombre recibido; cajetines internos mantienen 02/07/2026 y algunos textos de plantilla.","sourceFileSha256":"b42eb027b7bc0b14c38d1d13514f4899b58a732aa8d0ba2ccf10fa2fc3192890"} | provisional | [] | {"Cota inferior relativa (m)":-0.6,"Cota superior relativa (m)":0.2,"Cero absoluto de visualización (m)":286.1,"Estado del cero absoluto":"Provisional","Criterio":"Las cotas relativas proceden del dibujo; la equivalencia absoluta no está confirmada."} | {"boundingBoxM":{"min":[56.410096,51.141558,0.5],"max":[56.973538,51.705,1.3]},"extentsM":[0.563442,0.563442,0.8],"meshSurfaceM2":2.099998,"meshVolumeM3":0.2,"closedSolid":true,"basis":"Magnitudes de las mallas representadas, no cantidades certificadas de obra, compra o fabricación. Las partes pueden compartir superficies; no se suman como un despiece de materiales."} | {"profileId":"concrete_ha30","name":"Hormigón HA-30","materialName":"Hormigón HA-30","physicalMaterialStatus":"documentado","physicalMaterialSource":"Nota general de pedestales 2CED5","appearanceStatus":"criterio_visual","appearanceBasis":"Interpretación visual del material documental; el acabado, tono y parámetros PBR no son una especificación contractual.","note":"La apariencia gráfica no modifica ni confirma la especificación física del material."} | {"elementId":"found_0904_056a944bf0a536","ifcGuid":"2wtv$R4hLHywNGLwIesvLG","ifcClass":"IfcFooting","buildingId":"process_plant","buildingName":"Zona de separación de aire","sourceDocumentId":"LHD2609-JG00100-20260904","sourceRepresentationKind":"foundation"} | {"layerId":"foundations","layerName":"Cimentaciones","role":"Cimentación industrial","basis":"Clasificación por función del elemento; no modifica las especificaciones documentales."} | {"profileId":"concrete_ha30","name":"Hormigón HA-30","status":"criterio_visual","basis":"Interpretación visual del material documental; el acabado, tono y parámetros PBR no son una especificación contractual.","physicalMaterialUnchanged":true} | 0.2 | Hormigón HA-30 | Hormigón HA-30 | found_0904_056a944bf0a536 | Nota general de pedestales 2CED5 | documentado | concrete_ha30 | [0.658824,0.658824,0.623529] | 0.94 | Zona de separación de aire; BIM · Cimentaciones | 0.563442 | 0.563442 | 0.8 | 285.5 | 286.3 | SUP-C24 | [] | ["C24"] | ZD1 / DZ-2 | ["2CCA8","2CD60","2CCC7","2CD95","2CCB6","2CCB7","2CD84","2CEBA","2CE95"] | SUP-C24/Cimentación de soporte de tuberías C24 · pedestal de hormigón | foundation | Geometría de fabricante; implantación absoluta provisional |  | Cimentaciones de equipos y pedestales del fabricante · revisión recibida 04/09/2026 | 2CCA8, 2CD60, 2CCC7, 2CD95, 2CCB6, 2CCB7, 2CD84, 2CEBA, 2CE95 | -0.6 | 0.2 | 0.25 | Cotas relativas del dibujo. La equivalencia con un datum absoluto está pendiente. | Z del modelo = cota relativa + 1,10 m. Correspondencia provisional con 286,10 m; no es cota de obra confirmada. | Contornos y sección documentados por el fabricante | 0.5 | 0.5 | Material: Hormigón HA-30
Cimentación de soporte de tuberías C25 · cuerpo de hormigón | Parcela industrial Jinhong | Cimentación industrial | Cimentaciones de equipos y pedestales del fabricante · revisión recibida 04/09/2026 | 1.12689 | 1.12688 | 0.4 | 3.6 | 0.4 | process_plant | Zona de separación de aire | {"name":"Hormigón HA-30","status":"documentado","source":"Nota general de pedestales 2CED5"} | {"documented":[{"label":"Extensión local X","value":1.0,"unit":"m","source":"2CCDA, 2CD54, 2CCF2, 2CD96, 2CCE3, 2CCE4, 2CD78, 2CEBB, 2CE96","status":"derivada del contorno CAD"},{"label":"Extensión local Y","value":1.0,"unit":"m","source":"2CCDA, 2CD54, 2CCF2, 2CD96, 2CCE3, 2CCE4, 2CD78, 2CEBB, 2CE96","status":"derivada del contorno CAD"},{"label":"Cota inferior relativa adoptada","value":-1.0,"unit":"m","source":"ZD1 / DZ-1","status":"documentada"},{"label":"Cota superior relativa adoptada","value":-0.6,"unit":"m","source":"ZD1 / DZ-1","status":"documentada / separación por material"}],"geometry":[{"label":"Extensión de la malla en X","value":1.1268850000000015,"unit":"m","source":"Geometría releída del IFC; datum absoluto de proceso provisional","status":"derivado"},{"label":"Extensión de la malla en Y","value":1.1268849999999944,"unit":"m","source":"Geometría releída del IFC; datum absoluto de proceso provisional","status":"derivado"},{"label":"Extensión de la malla en Z","value":0.4,"unit":"m","source":"Geometría releída del IFC; datum absoluto de proceso provisional","status":"derivado"},{"label":"Cota inferior de visualización","value":285.1,"unit":"m","source":"Geometría releída del IFC; datum absoluto de proceso provisional","status":"derivado"},{"label":"Cota superior de visualización","value":285.5,"unit":"m","source":"Geometría releída del IFC; datum absoluto de proceso provisional","status":"derivado"}]} | {"documentId":"LHD2609-JG00100-20260904","title":"Cimentaciones de equipos y pedestales del fabricante · revisión recibida 04/09/2026","date":"2026-09-04","sheet":"ZD1 / DZ-1","fileName":"LHD2609-JG00100_20260904.dwg","revisionCaveat":"Fecha de revisión tomada del nombre recibido; cajetines internos mantienen 02/07/2026 y algunos textos de plantilla.","sourceFileSha256":"b42eb027b7bc0b14c38d1d13514f4899b58a732aa8d0ba2ccf10fa2fc3192890"} | provisional | [] | {"Cota inferior relativa (m)":-1.0,"Cota superior relativa (m)":-0.6,"Cero absoluto de visualización (m)":286.1,"Estado del cero absoluto":"Provisional","Criterio":"Las cotas relativas proceden del dibujo; la equivalencia absoluta no está confirmada."} | {"boundingBoxM":{"min":[60.181784,51.892369,0.1],"max":[61.308669,53.019254,0.5]},"extentsM":[1.126885,1.126885,0.4],"meshSurfaceM2":3.600001,"meshVolumeM3":0.4,"closedSolid":true,"basis":"Magnitudes de las mallas representadas, no cantidades certificadas de obra, compra o fabricación. Las partes pueden compartir superficies; no se suman como un despiece de materiales."} | {"profileId":"concrete_ha30","name":"Hormigón HA-30","materialName":"Hormigón HA-30","physicalMaterialStatus":"documentado","physicalMaterialSource":"Nota general de pedestales 2CED5","appearanceStatus":"criterio_visual","appearanceBasis":"Interpretación visual del material documental; el acabado, tono y parámetros PBR no son una especificación contractual.","note":"La apariencia gráfica no modifica ni confirma la especificación física del material."} | {"elementId":"found_0904_af4691d99d02ee","ifcGuid":"1EsMzxxrXTWfMZAnMwl6$e","ifcClass":"IfcFooting","buildingId":"process_plant","buildingName":"Zona de separación de aire","sourceDocumentId":"LHD2609-JG00100-20260904","sourceRepresentationKind":"foundation"} | {"layerId":"foundations","layerName":"Cimentaciones","role":"Cimentación industrial","basis":"Clasificación por función del elemento; no modifica las especificaciones documentales."} | {"profileId":"concrete_ha30","name":"Hormigón HA-30","status":"criterio_visual","basis":"Interpretación visual del material documental; el acabado, tono y parámetros PBR no son una especificación contractual.","physicalMaterialUnchanged":true} | 0.4 | Hormigón HA-30 | Hormigón HA-30 | found_0904_af4691d99d02ee | Nota general de pedestales 2CED5 | documentado | concrete_ha30 | [0.658824,0.658824,0.623529] | 0.94 | Zona de separación de aire; BIM · Cimentaciones | 1.12689 | 1.12688 | 0.4 | 285.1 | 285.5 | SUP-C25 | [] | ["C25"] | ZD1 / DZ-1 | ["2CCDA","2CD54","2CCF2","2CD96","2CCE3","2CCE4","2CD78","2CEBB","2CE96"] | SUP-C25/Cimentación de soporte de tuberías C25 · cuerpo de hormigón | foundation | Geometría de fabricante; implantación absoluta provisional |  | Cimentaciones de equipos y pedestales del fabricante · revisión recibida 04/09/2026 | 2CCDA, 2CD54, 2CCF2, 2CD96, 2CCE3, 2CCE4, 2CD78, 2CEBB, 2CE96 | -1 | -0.6 | 1 | Cotas relativas del dibujo. La equivalencia con un datum absoluto está pendiente. | Z del modelo = cota relativa + 1,10 m. Correspondencia provisional con 286,10 m; no es cota de obra confirmada. | Contornos y sección documentados por el fabricante | 1 | 1 | Material: Hormigón HA-30
Cimentación de soporte de tuberías C25 · pedestal de hormigón | Parcela industrial Jinhong | Cimentación industrial | Cimentaciones de equipos y pedestales del fabricante · revisión recibida 04/09/2026 | 0.507098 | 0.507098 | 0.8 | 1.845 | 0.162 | process_plant | Zona de separación de aire | {"name":"Hormigón HA-30","status":"documentado","source":"Nota general de pedestales 2CED5"} | {"documented":[{"label":"Extensión local X","value":0.45,"unit":"m","source":"2CCDA, 2CD54, 2CCF2, 2CD96, 2CCE3, 2CCE4, 2CD78, 2CEBB, 2CE96","status":"derivada del contorno CAD"},{"label":"Extensión local Y","value":0.45,"unit":"m","source":"2CCDA, 2CD54, 2CCF2, 2CD96, 2CCE3, 2CCE4, 2CD78, 2CEBB, 2CE96","status":"derivada del contorno CAD"},{"label":"Cota inferior relativa adoptada","value":-0.6,"unit":"m","source":"ZD1 / DZ-1","status":"documentada"},{"label":"Cota superior relativa adoptada","value":0.2,"unit":"m","source":"ZD1 / DZ-1","status":"documentada / separación por material"}],"geometry":[{"label":"Extensión de la malla en X","value":0.5070979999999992,"unit":"m","source":"Geometría releída del IFC; datum absoluto de proceso provisional","status":"derivado"},{"label":"Extensión de la malla en Y","value":0.5070979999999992,"unit":"m","source":"Geometría releída del IFC; datum absoluto de proceso provisional","status":"derivado"},{"label":"Extensión de la malla en Z","value":0.8,"unit":"m","source":"Geometría releída del IFC; datum absoluto de proceso provisional","status":"derivado"},{"label":"Cota inferior de visualización","value":285.5,"unit":"m","source":"Geometría releída del IFC; datum absoluto de proceso provisional","status":"derivado"},{"label":"Cota superior de visualización","value":286.3,"unit":"m","source":"Geometría releída del IFC; datum absoluto de proceso provisional","status":"derivado"}]} | {"documentId":"LHD2609-JG00100-20260904","title":"Cimentaciones de equipos y pedestales del fabricante · revisión recibida 04/09/2026","date":"2026-09-04","sheet":"ZD1 / DZ-1","fileName":"LHD2609-JG00100_20260904.dwg","revisionCaveat":"Fecha de revisión tomada del nombre recibido; cajetines internos mantienen 02/07/2026 y algunos textos de plantilla.","sourceFileSha256":"b42eb027b7bc0b14c38d1d13514f4899b58a732aa8d0ba2ccf10fa2fc3192890"} | provisional | [] | {"Cota inferior relativa (m)":-0.6,"Cota superior relativa (m)":0.2,"Cero absoluto de visualización (m)":286.1,"Estado del cero absoluto":"Provisional","Criterio":"Las cotas relativas proceden del dibujo; la equivalencia absoluta no está confirmada."} | {"boundingBoxM":{"min":[60.491677,52.202262,0.5],"max":[60.998775,52.70936,1.3]},"extentsM":[0.507098,0.507098,0.8],"meshSurfaceM2":1.844999,"meshVolumeM3":0.162,"closedSolid":true,"basis":"Magnitudes de las mallas representadas, no cantidades certificadas de obra, compra o fabricación. Las partes pueden compartir superficies; no se suman como un despiece de materiales."} | {"profileId":"concrete_ha30","name":"Hormigón HA-30","materialName":"Hormigón HA-30","physicalMaterialStatus":"documentado","physicalMaterialSource":"Nota general de pedestales 2CED5","appearanceStatus":"criterio_visual","appearanceBasis":"Interpretación visual del material documental; el acabado, tono y parámetros PBR no son una especificación contractual.","note":"La apariencia gráfica no modifica ni confirma la especificación física del material."} | {"elementId":"found_0904_5853339dc5af60","ifcGuid":"3XLTLylHLP$PU3ot3Sf3GA","ifcClass":"IfcFooting","buildingId":"process_plant","buildingName":"Zona de separación de aire","sourceDocumentId":"LHD2609-JG00100-20260904","sourceRepresentationKind":"foundation"} | {"layerId":"foundations","layerName":"Cimentaciones","role":"Cimentación industrial","basis":"Clasificación por función del elemento; no modifica las especificaciones documentales."} | {"profileId":"concrete_ha30","name":"Hormigón HA-30","status":"criterio_visual","basis":"Interpretación visual del material documental; el acabado, tono y parámetros PBR no son una especificación contractual.","physicalMaterialUnchanged":true} | 0.162 | Hormigón HA-30 | Hormigón HA-30 | found_0904_5853339dc5af60 | Nota general de pedestales 2CED5 | documentado | concrete_ha30 | [0.658824,0.658824,0.623529] | 0.94 | Zona de separación de aire; BIM · Cimentaciones | 0.507098 | 0.507098 | 0.8 | 285.5 | 286.3 | SUP-C25 | [] | ["C25"] | ZD1 / DZ-1 | ["2CCDA","2CD54","2CCF2","2CD96","2CCE3","2CCE4","2CD78","2CEBB","2CE96"] | SUP-C25/Cimentación de soporte de tuberías C25 · pedestal de hormigón | foundation | Geometría de fabricante; implantación absoluta provisional |  | Cimentaciones de equipos y pedestales del fabricante · revisión recibida 04/09/2026 | 2CCDA, 2CD54, 2CCF2, 2CD96, 2CCE3, 2CCE4, 2CD78, 2CEBB, 2CE96 | -0.6 | 0.2 | 0.2025 | Cotas relativas del dibujo. La equivalencia con un datum absoluto está pendiente. | Z del modelo = cota relativa + 1,10 m. Correspondencia provisional con 286,10 m; no es cota de obra confirmada. | Contornos y sección documentados por el fabricante | 0.45 | 0.45 | Material: Hormigón HA-30
Cimentación de soporte de tuberías C26 · cuerpo de hormigón | Parcela industrial Jinhong | Cimentación industrial | Cimentaciones de equipos y pedestales del fabricante · revisión recibida 04/09/2026 | 1.12689 | 1.12689 | 0.4 | 3.6 | 0.4 | process_plant | Zona de separación de aire | {"name":"Hormigón HA-30","status":"documentado","source":"Nota general de pedestales 2CED5"} | {"documented":[{"label":"Extensión local X","value":1.0,"unit":"m","source":"2CCDB, 2CD55, 2CCF3, 2CD97, 2CCE2, 2CCE5, 2CD79, 2CEBC, 2CE97","status":"derivada del contorno CAD"},{"label":"Extensión local Y","value":1.0,"unit":"m","source":"2CCDB, 2CD55, 2CCF3, 2CD97, 2CCE2, 2CCE5, 2CD79, 2CEBC, 2CE97","status":"derivada del contorno CAD"},{"label":"Cota inferior relativa adoptada","value":-1.0,"unit":"m","source":"ZD1 / DZ-1","status":"documentada"},{"label":"Cota superior relativa adoptada","value":-0.6,"unit":"m","source":"ZD1 / DZ-1","status":"documentada / separación por material"}],"geometry":[{"label":"Extensión de la malla en X","value":1.1268850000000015,"unit":"m","source":"Geometría releída del IFC; datum absoluto de proceso provisional","status":"derivado"},{"label":"Extensión de la malla en Y","value":1.1268850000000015,"unit":"m","source":"Geometría releída del IFC; datum absoluto de proceso provisional","status":"derivado"},{"label":"Extensión de la malla en Z","value":0.4,"unit":"m","source":"Geometría releída del IFC; datum absoluto de proceso provisional","status":"derivado"},{"label":"Cota inferior de visualización","value":285.1,"unit":"m","source":"Geometría releída del IFC; datum absoluto de proceso provisional","status":"derivado"},{"label":"Cota superior de visualización","value":285.5,"unit":"m","source":"Geometría releída del IFC; datum absoluto de proceso provisional","status":"derivado"}]} | {"documentId":"LHD2609-JG00100-20260904","title":"Cimentaciones de equipos y pedestales del fabricante · revisión recibida 04/09/2026","date":"2026-09-04","sheet":"ZD1 / DZ-1","fileName":"LHD2609-JG00100_20260904.dwg","revisionCaveat":"Fecha de revisión tomada del nombre recibido; cajetines internos mantienen 02/07/2026 y algunos textos de plantilla.","sourceFileSha256":"b42eb027b7bc0b14c38d1d13514f4899b58a732aa8d0ba2ccf10fa2fc3192890"} | provisional | [] | {"Cota inferior relativa (m)":-1.0,"Cota superior relativa (m)":-0.6,"Cero absoluto de visualización (m)":286.1,"Estado del cero absoluto":"Provisional","Criterio":"Las cotas relativas proceden del dibujo; la equivalencia absoluta no está confirmada."} | {"boundingBoxM":{"min":[61.915475,51.654012,0.1],"max":[63.04236,52.780897,0.5]},"extentsM":[1.126885,1.126885,0.4],"meshSurfaceM2":3.600001,"meshVolumeM3":0.4,"closedSolid":true,"basis":"Magnitudes de las mallas representadas, no cantidades certificadas de obra, compra o fabricación. Las partes pueden compartir superficies; no se suman como un despiece de materiales."} | {"profileId":"concrete_ha30","name":"Hormigón HA-30","materialName":"Hormigón HA-30","physicalMaterialStatus":"documentado","physicalMaterialSource":"Nota general de pedestales 2CED5","appearanceStatus":"criterio_visual","appearanceBasis":"Interpretación visual del material documental; el acabado, tono y parámetros PBR no son una especificación contractual.","note":"La apariencia gráfica no modifica ni confirma la especificación física del material."} | {"elementId":"found_0904_d36d26f7aefe4b","ifcGuid":"16Zim06rvSX9pAD8JBn6BV","ifcClass":"IfcFooting","buildingId":"process_plant","buildingName":"Zona de separación de aire","sourceDocumentId":"LHD2609-JG00100-20260904","sourceRepresentationKind":"foundation"} | {"layerId":"foundations","layerName":"Cimentaciones","role":"Cimentación industrial","basis":"Clasificación por función del elemento; no modifica las especificaciones documentales."} | {"profileId":"concrete_ha30","name":"Hormigón HA-30","status":"criterio_visual","basis":"Interpretación visual del material documental; el acabado, tono y parámetros PBR no son una especificación contractual.","physicalMaterialUnchanged":true} | 0.4 | Hormigón HA-30 | Hormigón HA-30 | found_0904_d36d26f7aefe4b | Nota general de pedestales 2CED5 | documentado | concrete_ha30 | [0.658824,0.658824,0.623529] | 0.94 | Zona de separación de aire; BIM · Cimentaciones | 1.12689 | 1.12689 | 0.4 | 285.1 | 285.5 | SUP-C26 | [] | ["C26"] | ZD1 / DZ-1 | ["2CCDB","2CD55","2CCF3","2CD97","2CCE2","2CCE5","2CD79","2CEBC","2CE97"] | SUP-C26/Cimentación de soporte de tuberías C26 · cuerpo de hormigón | foundation | Geometría de fabricante; implantación absoluta provisional |  | Cimentaciones de equipos y pedestales del fabricante · revisión recibida 04/09/2026 | 2CCDB, 2CD55, 2CCF3, 2CD97, 2CCE2, 2CCE5, 2CD79, 2CEBC, 2CE97 | -1 | -0.6 | 1 | Cotas relativas del dibujo. La equivalencia con un datum absoluto está pendiente. | Z del modelo = cota relativa + 1,10 m. Correspondencia provisional con 286,10 m; no es cota de obra confirmada. | Contornos y sección documentados por el fabricante | 1 | 1 | Material: Hormigón HA-30
Cimentación de soporte de tuberías C26 · pedestal de hormigón | Parcela industrial Jinhong | Cimentación industrial | Cimentaciones de equipos y pedestales del fabricante · revisión recibida 04/09/2026 | 0.507098 | 0.507098 | 0.8 | 1.845 | 0.162 | process_plant | Zona de separación de aire | {"name":"Hormigón HA-30","status":"documentado","source":"Nota general de pedestales 2CED5"} | {"documented":[{"label":"Extensión local X","value":0.45,"unit":"m","source":"2CCDB, 2CD55, 2CCF3, 2CD97, 2CCE2, 2CCE5, 2CD79, 2CEBC, 2CE97","status":"derivada del contorno CAD"},{"label":"Extensión local Y","value":0.45,"unit":"m","source":"2CCDB, 2CD55, 2CCF3, 2CD97, 2CCE2, 2CCE5, 2CD79, 2CEBC, 2CE97","status":"derivada del contorno CAD"},{"label":"Cota inferior relativa adoptada","value":-0.6,"unit":"m","source":"ZD1 / DZ-1","status":"documentada"},{"label":"Cota superior relativa adoptada","value":0.2,"unit":"m","source":"ZD1 / DZ-1","status":"documentada / separación por material"}],"geometry":[{"label":"Extensión de la malla en X","value":0.5070979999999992,"unit":"m","source":"Geometría releída del IFC; datum absoluto de proceso provisional","status":"derivado"},{"label":"Extensión de la malla en Y","value":0.5070980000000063,"unit":"m","source":"Geometría releída del IFC; datum absoluto de proceso provisional","status":"derivado"},{"label":"Extensión de la malla en Z","value":0.8,"unit":"m","source":"Geometría releída del IFC; datum absoluto de proceso provisional","status":"derivado"},{"label":"Cota inferior de visualización","value":285.5,"unit":"m","source":"Geometría releída del IFC; datum absoluto de proceso provisional","status":"derivado"},{"label":"Cota superior de visualización","value":286.3,"unit":"m","source":"Geometría releída del IFC; datum absoluto de proceso provisional","status":"derivado"}]} | {"documentId":"LHD2609-JG00100-20260904","title":"Cimentaciones de equipos y pedestales del fabricante · revisión recibida 04/09/2026","date":"2026-09-04","sheet":"ZD1 / DZ-1","fileName":"LHD2609-JG00100_20260904.dwg","revisionCaveat":"Fecha de revisión tomada del nombre recibido; cajetines internos mantienen 02/07/2026 y algunos textos de plantilla.","sourceFileSha256":"b42eb027b7bc0b14c38d1d13514f4899b58a732aa8d0ba2ccf10fa2fc3192890"} | provisional | [] | {"Cota inferior relativa (m)":-0.6,"Cota superior relativa (m)":0.2,"Cero absoluto de visualización (m)":286.1,"Estado del cero absoluto":"Provisional","Criterio":"Las cotas relativas proceden del dibujo; la equivalencia absoluta no está confirmada."} | {"boundingBoxM":{"min":[62.225369,51.963905,0.5],"max":[62.732467,52.471003,1.3]},"extentsM":[0.507098,0.507098,0.8],"meshSurfaceM2":1.845,"meshVolumeM3":0.162,"closedSolid":true,"basis":"Magnitudes de las mallas representadas, no cantidades certificadas de obra, compra o fabricación. Las partes pueden compartir superficies; no se suman como un despiece de materiales."} | {"profileId":"concrete_ha30","name":"Hormigón HA-30","materialName":"Hormigón HA-30","physicalMaterialStatus":"documentado","physicalMaterialSource":"Nota general de pedestales 2CED5","appearanceStatus":"criterio_visual","appearanceBasis":"Interpretación visual del material documental; el acabado, tono y parámetros PBR no son una especificación contractual.","note":"La apariencia gráfica no modifica ni confirma la especificación física del material."} | {"elementId":"found_0904_9b365ec6dae3f5","ifcGuid":"1FWTYYsdzNOhs8XE7a4fc5","ifcClass":"IfcFooting","buildingId":"process_plant","buildingName":"Zona de separación de aire","sourceDocumentId":"LHD2609-JG00100-20260904","sourceRepresentationKind":"foundation"} | {"layerId":"foundations","layerName":"Cimentaciones","role":"Cimentación industrial","basis":"Clasificación por función del elemento; no modifica las especificaciones documentales."} | {"profileId":"concrete_ha30","name":"Hormigón HA-30","status":"criterio_visual","basis":"Interpretación visual del material documental; el acabado, tono y parámetros PBR no son una especificación contractual.","physicalMaterialUnchanged":true} | 0.162 | Hormigón HA-30 | Hormigón HA-30 | found_0904_9b365ec6dae3f5 | Nota general de pedestales 2CED5 | documentado | concrete_ha30 | [0.658824,0.658824,0.623529] | 0.94 | Zona de separación de aire; BIM · Cimentaciones | 0.507098 | 0.507098 | 0.8 | 285.5 | 286.3 | SUP-C26 | [] | ["C26"] | ZD1 / DZ-1 | ["2CCDB","2CD55","2CCF3","2CD97","2CCE2","2CCE5","2CD79","2CEBC","2CE97"] | SUP-C26/Cimentación de soporte de tuberías C26 · pedestal de hormigón | foundation | Geometría de fabricante; implantación absoluta provisional |  | Cimentaciones de equipos y pedestales del fabricante · revisión recibida 04/09/2026 | 2CCDB, 2CD55, 2CCF3, 2CD97, 2CCE2, 2CCE5, 2CD79, 2CEBC, 2CE97 | -0.6 | 0.2 | 0.2025 | Cotas relativas del dibujo. La equivalencia con un datum absoluto está pendiente. | Z del modelo = cota relativa + 1,10 m. Correspondencia provisional con 286,10 m; no es cota de obra confirmada. | Contornos y sección documentados por el fabricante | 0.45 | 0.45 | Material: Hormigón HA-30
Cimentación de soporte de tuberías C27 · cuerpo de hormigón | Parcela industrial Jinhong | Cimentación industrial | Cimentaciones de equipos y pedestales del fabricante · revisión recibida 04/09/2026 | 1.12689 | 1.12689 | 0.4 | 3.6 | 0.4 | process_plant | Zona de separación de aire | {"name":"Hormigón HA-30","status":"documentado","source":"Nota general de pedestales 2CED5"} | {"documented":[{"label":"Extensión local X","value":1.0,"unit":"m","source":"2CCDC, 2CD56, 2CCF4, 2CD98, 2CCE6, 2CCE8, 2CD7A, 2CEBD, 2CE98","status":"derivada del contorno CAD"},{"label":"Extensión local Y","value":1.0,"unit":"m","source":"2CCDC, 2CD56, 2CCF4, 2CD98, 2CCE6, 2CCE8, 2CD7A, 2CEBD, 2CE98","status":"derivada del contorno CAD"},{"label":"Cota inferior relativa adoptada","value":-1.0,"unit":"m","source":"ZD1 / DZ-1","status":"documentada"},{"label":"Cota superior relativa adoptada","value":-0.6,"unit":"m","source":"ZD1 / DZ-1","status":"documentada / separación por material"}],"geometry":[{"label":"Extensión de la malla en X","value":1.1268850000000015,"unit":"m","source":"Geometría releída del IFC; datum absoluto de proceso provisional","status":"derivado"},{"label":"Extensión de la malla en Y","value":1.1268850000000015,"unit":"m","source":"Geometría releída del IFC; datum absoluto de proceso provisional","status":"derivado"},{"label":"Extensión de la malla en Z","value":0.4,"unit":"m","source":"Geometría releída del IFC; datum absoluto de proceso provisional","status":"derivado"},{"label":"Cota inferior de visualización","value":285.1,"unit":"m","source":"Geometría releída del IFC; datum absoluto de proceso provisional","status":"derivado"},{"label":"Cota superior de visualización","value":285.5,"unit":"m","source":"Geometría releída del IFC; datum absoluto de proceso provisional","status":"derivado"}]} | {"documentId":"LHD2609-JG00100-20260904","title":"Cimentaciones de equipos y pedestales del fabricante · revisión recibida 04/09/2026","date":"2026-09-04","sheet":"ZD1 / DZ-1","fileName":"LHD2609-JG00100_20260904.dwg","revisionCaveat":"Fecha de revisión tomada del nombre recibido; cajetines internos mantienen 02/07/2026 y algunos textos de plantilla.","sourceFileSha256":"b42eb027b7bc0b14c38d1d13514f4899b58a732aa8d0ba2ccf10fa2fc3192890"} | provisional | [] | {"Cota inferior relativa (m)":-1.0,"Cota superior relativa (m)":-0.6,"Cero absoluto de visualización (m)":286.1,"Estado del cero absoluto":"Provisional","Criterio":"Las cotas relativas proceden del dibujo; la equivalencia absoluta no está confirmada."} | {"boundingBoxM":{"min":[59.943427,50.158677,0.1],"max":[61.070312,51.285562,0.5]},"extentsM":[1.126885,1.126885,0.4],"meshSurfaceM2":3.600001,"meshVolumeM3":0.4,"closedSolid":true,"basis":"Magnitudes de las mallas representadas, no cantidades certificadas de obra, compra o fabricación. Las partes pueden compartir superficies; no se suman como un despiece de materiales."} | {"profileId":"concrete_ha30","name":"Hormigón HA-30","materialName":"Hormigón HA-30","physicalMaterialStatus":"documentado","physicalMaterialSource":"Nota general de pedestales 2CED5","appearanceStatus":"criterio_visual","appearanceBasis":"Interpretación visual del material documental; el acabado, tono y parámetros PBR no son una especificación contractual.","note":"La apariencia gráfica no modifica ni confirma la especificación física del material."} | {"elementId":"found_0904_a793484b58d0ab","ifcGuid":"0kc0xAS2PMLeQpbA7MMS2E","ifcClass":"IfcFooting","buildingId":"process_plant","buildingName":"Zona de separación de aire","sourceDocumentId":"LHD2609-JG00100-20260904","sourceRepresentationKind":"foundation"} | {"layerId":"foundations","layerName":"Cimentaciones","role":"Cimentación industrial","basis":"Clasificación por función del elemento; no modifica las especificaciones documentales."} | {"profileId":"concrete_ha30","name":"Hormigón HA-30","status":"criterio_visual","basis":"Interpretación visual del material documental; el acabado, tono y parámetros PBR no son una especificación contractual.","physicalMaterialUnchanged":true} | 0.4 | Hormigón HA-30 | Hormigón HA-30 | found_0904_a793484b58d0ab | Nota general de pedestales 2CED5 | documentado | concrete_ha30 | [0.658824,0.658824,0.623529] | 0.94 | Zona de separación de aire; BIM · Cimentaciones | 1.12689 | 1.12689 | 0.4 | 285.1 | 285.5 | SUP-C27 | [] | ["C27"] | ZD1 / DZ-1 | ["2CCDC","2CD56","2CCF4","2CD98","2CCE6","2CCE8","2CD7A","2CEBD","2CE98"] | SUP-C27/Cimentación de soporte de tuberías C27 · cuerpo de hormigón | foundation | Geometría de fabricante; implantación absoluta provisional |  | Cimentaciones de equipos y pedestales del fabricante · revisión recibida 04/09/2026 | 2CCDC, 2CD56, 2CCF4, 2CD98, 2CCE6, 2CCE8, 2CD7A, 2CEBD, 2CE98 | -1 | -0.6 | 1 | Cotas relativas del dibujo. La equivalencia con un datum absoluto está pendiente. | Z del modelo = cota relativa + 1,10 m. Correspondencia provisional con 286,10 m; no es cota de obra confirmada. | Contornos y sección documentados por el fabricante | 1 | 1 | Material: Hormigón HA-30
Cimentación de soporte de tuberías C27 · pedestal de hormigón | Parcela industrial Jinhong | Cimentación industrial | Cimentaciones de equipos y pedestales del fabricante · revisión recibida 04/09/2026 | 0.507098 | 0.507098 | 0.8 | 1.845 | 0.162 | process_plant | Zona de separación de aire | {"name":"Hormigón HA-30","status":"documentado","source":"Nota general de pedestales 2CED5"} | {"documented":[{"label":"Extensión local X","value":0.45,"unit":"m","source":"2CCDC, 2CD56, 2CCF4, 2CD98, 2CCE6, 2CCE8, 2CD7A, 2CEBD, 2CE98","status":"derivada del contorno CAD"},{"label":"Extensión local Y","value":0.45,"unit":"m","source":"2CCDC, 2CD56, 2CCF4, 2CD98, 2CCE6, 2CCE8, 2CD7A, 2CEBD, 2CE98","status":"derivada del contorno CAD"},{"label":"Cota inferior relativa adoptada","value":-0.6,"unit":"m","source":"ZD1 / DZ-1","status":"documentada"},{"label":"Cota superior relativa adoptada","value":0.2,"unit":"m","source":"ZD1 / DZ-1","status":"documentada / separación por material"}],"geometry":[{"label":"Extensión de la malla en X","value":0.5070979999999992,"unit":"m","source":"Geometría releída del IFC; datum absoluto de proceso provisional","status":"derivado"},{"label":"Extensión de la malla en Y","value":0.5070980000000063,"unit":"m","source":"Geometría releída del IFC; datum absoluto de proceso provisional","status":"derivado"},{"label":"Extensión de la malla en Z","value":0.8,"unit":"m","source":"Geometría releída del IFC; datum absoluto de proceso provisional","status":"derivado"},{"label":"Cota inferior de visualización","value":285.5,"unit":"m","source":"Geometría releída del IFC; datum absoluto de proceso provisional","status":"derivado"},{"label":"Cota superior de visualización","value":286.3,"unit":"m","source":"Geometría releída del IFC; datum absoluto de proceso provisional","status":"derivado"}]} | {"documentId":"LHD2609-JG00100-20260904","title":"Cimentaciones de equipos y pedestales del fabricante · revisión recibida 04/09/2026","date":"2026-09-04","sheet":"ZD1 / DZ-1","fileName":"LHD2609-JG00100_20260904.dwg","revisionCaveat":"Fecha de revisión tomada del nombre recibido; cajetines internos mantienen 02/07/2026 y algunos textos de plantilla.","sourceFileSha256":"b42eb027b7bc0b14c38d1d13514f4899b58a732aa8d0ba2ccf10fa2fc3192890"} | provisional | [] | {"Cota inferior relativa (m)":-0.6,"Cota superior relativa (m)":0.2,"Cero absoluto de visualización (m)":286.1,"Estado del cero absoluto":"Provisional","Criterio":"Las cotas relativas proceden del dibujo; la equivalencia absoluta no está confirmada."} | {"boundingBoxM":{"min":[60.25332,50.468571,0.5],"max":[60.760418,50.975669,1.3]},"extentsM":[0.507098,0.507098,0.8],"meshSurfaceM2":1.845,"meshVolumeM3":0.162,"closedSolid":true,"basis":"Magnitudes de las mallas representadas, no cantidades certificadas de obra, compra o fabricación. Las partes pueden compartir superficies; no se suman como un despiece de materiales."} | {"profileId":"concrete_ha30","name":"Hormigón HA-30","materialName":"Hormigón HA-30","physicalMaterialStatus":"documentado","physicalMaterialSource":"Nota general de pedestales 2CED5","appearanceStatus":"criterio_visual","appearanceBasis":"Interpretación visual del material documental; el acabado, tono y parámetros PBR no son una especificación contractual.","note":"La apariencia gráfica no modifica ni confirma la especificación física del material."} | {"elementId":"found_0904_6e142458f912df","ifcGuid":"1wweYwAmHMPfcAQ1liwinC","ifcClass":"IfcFooting","buildingId":"process_plant","buildingName":"Zona de separación de aire","sourceDocumentId":"LHD2609-JG00100-20260904","sourceRepresentationKind":"foundation"} | {"layerId":"foundations","layerName":"Cimentaciones","role":"Cimentación industrial","basis":"Clasificación por función del elemento; no modifica las especificaciones documentales."} | {"profileId":"concrete_ha30","name":"Hormigón HA-30","status":"criterio_visual","basis":"Interpretación visual del material documental; el acabado, tono y parámetros PBR no son una especificación contractual.","physicalMaterialUnchanged":true} | 0.162 | Hormigón HA-30 | Hormigón HA-30 | found_0904_6e142458f912df | Nota general de pedestales 2CED5 | documentado | concrete_ha30 | [0.658824,0.658824,0.623529] | 0.94 | Zona de separación de aire; BIM · Cimentaciones | 0.507098 | 0.507098 | 0.8 | 285.5 | 286.3 | SUP-C27 | [] | ["C27"] | ZD1 / DZ-1 | ["2CCDC","2CD56","2CCF4","2CD98","2CCE6","2CCE8","2CD7A","2CEBD","2CE98"] | SUP-C27/Cimentación de soporte de tuberías C27 · pedestal de hormigón | foundation | Geometría de fabricante; implantación absoluta provisional |  | Cimentaciones de equipos y pedestales del fabricante · revisión recibida 04/09/2026 | 2CCDC, 2CD56, 2CCF4, 2CD98, 2CCE6, 2CCE8, 2CD7A, 2CEBD, 2CE98 | -0.6 | 0.2 | 0.2025 | Cotas relativas del dibujo. La equivalencia con un datum absoluto está pendiente. | Z del modelo = cota relativa + 1,10 m. Correspondencia provisional con 286,10 m; no es cota de obra confirmada. | Contornos y sección documentados por el fabricante | 0.45 | 0.45 | Material: Hormigón HA-30
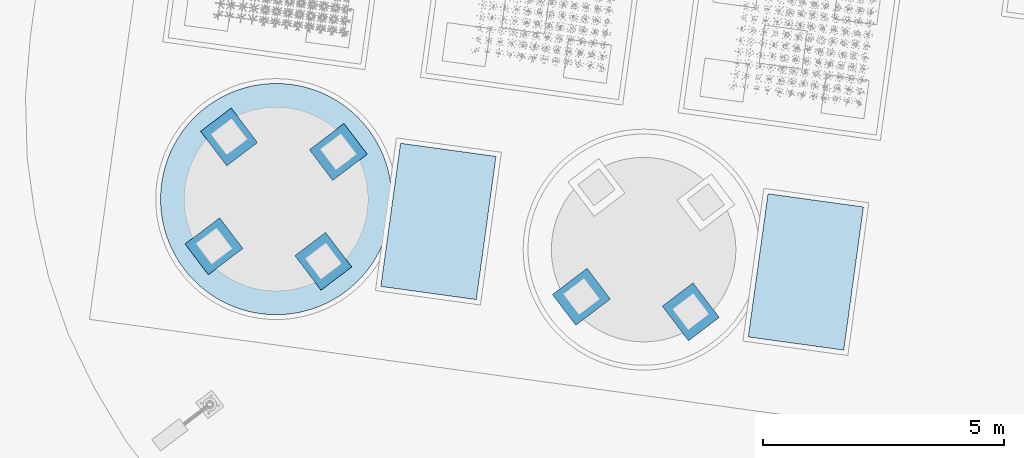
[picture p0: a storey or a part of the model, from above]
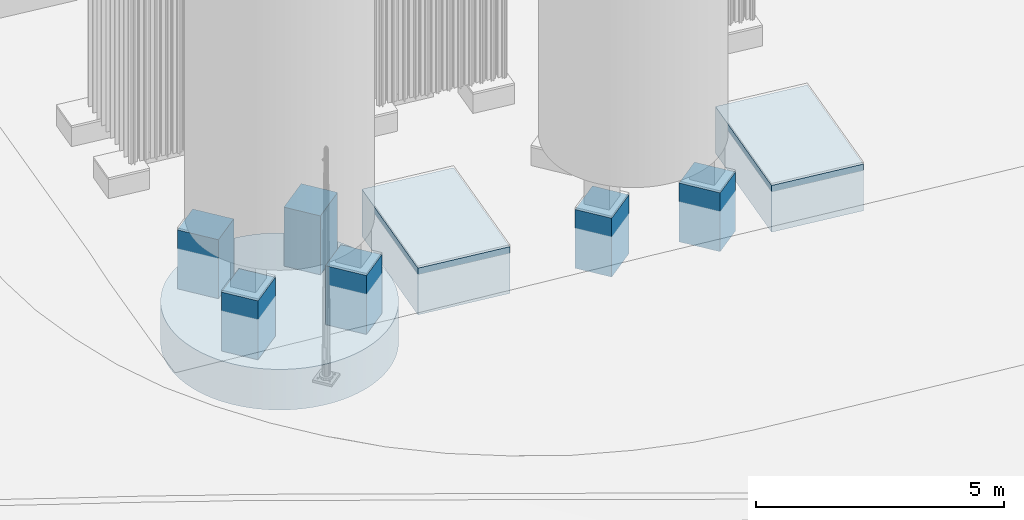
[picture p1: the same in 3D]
Properties of the parts of a building model (IFC4), part 83 of 134

# IfcFooting (214)
Name | In | Description = category = Categoria = Funcion | Document | ExtensionX (m) | ExtensionY (m) | ExtensionZ (m) | SuperficieDeLaMalla (m2) | VolumenGeometrico (m3) | buildingId | buildingName | material | dimensions | JH_InformacionBIM, source = DocumentoFuente | JH_InformacionBIM, status = EstadoDeInformacion | issues = IncidenciasPendientes | positioning = PosicionYEstado | geometryMetrics | materialAppearance | visualizationIdentity | classification | appearance | Volumen geométrico (m³) | JH_Trazabilidad, Material = name | Acabado de visualización = Acabado | Identificador | JH_EvidenciaDeMaterial, source | JH_EvidenciaDeMaterial, status | Perfil | ColorRGB | Rugosidad | Group | Extensión de la malla en X (m) | Extensión de la malla en Y (m) | Extensión de la malla en Z (m) = Espesor o altura real de sección (m) | Cota inferior de visualización (m) | Cota superior de visualización (m) | assemblyId = Conjunto de cimentación | equipmentIds | supportPositionIds | sectionRef = Sección de referencia | sourceCadHandles | stableElementKey | representationKind | geometryStatus | Equipos asociados | Documento de origen | Identificadores CAD de referencia | Cota inferior relativa (m) = Cota inferior relativa adoptada (m) | Cota superior relativa (m) = Cota superior relativa adoptada (m) | Área de planta (m²) | Referencia vertical | Implantación para visualización | Estado de la geometría | Extensión local X (m) | Extensión local Y (m) | Incidencias de origen
Cimentación de soporte de tuberías C28 · cuerpo de hormigón | Parcela industrial Jinhong | Cimentación industrial | Cimentaciones de equipos y pedestales del fabricante · revisión recibida 04/09/2026 | 1.12689 | 1.12689 | 0.4 | 3.6 | 0.4 | process_plant | Zona de separación de aire | {"name":"Hormigón HA-30","status":"documentado","source":"Nota general de pedestales 2CED5"} | {"documented":[{"label":"Extensión local X","value":1.0,"unit":"m","source":"2CCDD, 2CD57, 2CCF5, 2CD99, 2CCE7, 2CCE9, 2CD7B, 2CEBE, 2CE99","status":"derivada del contorno CAD"},{"label":"Extensión local Y","value":1.0,"unit":"m","source":"2CCDD, 2CD57, 2CCF5, 2CD99, 2CCE7, 2CCE9, 2CD7B, 2CEBE, 2CE99","status":"derivada del contorno CAD"},{"label":"Cota inferior relativa adoptada","value":-1.0,"unit":"m","source":"ZD1 / DZ-1","status":"documentada"},{"label":"Cota superior relativa adoptada","value":-0.6,"unit":"m","source":"ZD1 / DZ-1","status":"documentada / separación por material"}],"geometry":[{"label":"Extensión de la malla en X","value":1.1268850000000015,"unit":"m","source":"Geometría releída del IFC; datum absoluto de proceso provisional","status":"derivado"},{"label":"Extensión de la malla en Y","value":1.1268850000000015,"unit":"m","source":"Geometría releída del IFC; datum absoluto de proceso provisional","status":"derivado"},{"label":"Extensión de la malla en Z","value":0.4,"unit":"m","source":"Geometría releída del IFC; datum absoluto de proceso provisional","status":"derivado"},{"label":"Cota inferior de visualización","value":285.1,"unit":"m","source":"Geometría releída del IFC; datum absoluto de proceso provisional","status":"derivado"},{"label":"Cota superior de visualización","value":285.5,"unit":"m","source":"Geometría releída del IFC; datum absoluto de proceso provisional","status":"derivado"}]} | {"documentId":"LHD2609-JG00100-20260904","title":"Cimentaciones de equipos y pedestales del fabricante · revisión recibida 04/09/2026","date":"2026-09-04","sheet":"ZD1 / DZ-1","fileName":"LHD2609-JG00100_20260904.dwg","revisionCaveat":"Fecha de revisión tomada del nombre recibido; cajetines internos mantienen 02/07/2026 y algunos textos de plantilla.","sourceFileSha256":"b42eb027b7bc0b14c38d1d13514f4899b58a732aa8d0ba2ccf10fa2fc3192890"} | provisional | [] | {"Cota inferior relativa (m)":-1.0,"Cota superior relativa (m)":-0.6,"Cero absoluto de visualización (m)":286.1,"Estado del cero absoluto":"Provisional","Criterio":"Las cotas relativas proceden del dibujo; la equivalencia absoluta no está confirmada."} | {"boundingBoxM":{"min":[61.677118,49.92032,0.1],"max":[62.804003,51.047205,0.5]},"extentsM":[1.126885,1.126885,0.4],"meshSurfaceM2":3.600001,"meshVolumeM3":0.4,"closedSolid":true,"basis":"Magnitudes de las mallas representadas, no cantidades certificadas de obra, compra o fabricación. Las partes pueden compartir superficies; no se suman como un despiece de materiales."} | {"profileId":"concrete_ha30","name":"Hormigón HA-30","materialName":"Hormigón HA-30","physicalMaterialStatus":"documentado","physicalMaterialSource":"Nota general de pedestales 2CED5","appearanceStatus":"criterio_visual","appearanceBasis":"Interpretación visual del material documental; el acabado, tono y parámetros PBR no son una especificación contractual.","note":"La apariencia gráfica no modifica ni confirma la especificación física del material."} | {"elementId":"found_0904_2ff729696f79d9","ifcGuid":"3yuMNIVmXTkAAQxJ03GqrG","ifcClass":"IfcFooting","buildingId":"process_plant","buildingName":"Zona de separación de aire","sourceDocumentId":"LHD2609-JG00100-20260904","sourceRepresentationKind":"foundation"} | {"layerId":"foundations","layerName":"Cimentaciones","role":"Cimentación industrial","basis":"Clasificación por función del elemento; no modifica las especificaciones documentales."} | {"profileId":"concrete_ha30","name":"Hormigón HA-30","status":"criterio_visual","basis":"Interpretación visual del material documental; el acabado, tono y parámetros PBR no son una especificación contractual.","physicalMaterialUnchanged":true} | 0.4 | Hormigón HA-30 | Hormigón HA-30 | found_0904_2ff729696f79d9 | Nota general de pedestales 2CED5 | documentado | concrete_ha30 | [0.658824,0.658824,0.623529] | 0.94 | Zona de separación de aire; BIM · Cimentaciones | 1.12689 | 1.12689 | 0.4 | 285.1 | 285.5 | SUP-C28 | [] | ["C28"] | ZD1 / DZ-1 | ["2CCDD","2CD57","2CCF5","2CD99","2CCE7","2CCE9","2CD7B","2CEBE","2CE99"] | SUP-C28/Cimentación de soporte de tuberías C28 · cuerpo de hormigón | foundation | Geometría de fabricante; implantación absoluta provisional |  | Cimentaciones de equipos y pedestales del fabricante · revisión recibida 04/09/2026 | 2CCDD, 2CD57, 2CCF5, 2CD99, 2CCE7, 2CCE9, 2CD7B, 2CEBE, 2CE99 | -1 | -0.6 | 1 | Cotas relativas del dibujo. La equivalencia con un datum absoluto está pendiente. | Z del modelo = cota relativa + 1,10 m. Correspondencia provisional con 286,10 m; no es cota de obra confirmada. | Contornos y sección documentados por el fabricante | 1 | 1 | Material: Hormigón HA-30
Cimentación de soporte de tuberías C28 · pedestal de hormigón | Parcela industrial Jinhong | Cimentación industrial | Cimentaciones de equipos y pedestales del fabricante · revisión recibida 04/09/2026 | 0.507098 | 0.507098 | 0.8 | 1.845 | 0.162 | process_plant | Zona de separación de aire | {"name":"Hormigón HA-30","status":"documentado","source":"Nota general de pedestales 2CED5"} | {"documented":[{"label":"Extensión local X","value":0.45,"unit":"m","source":"2CCDD, 2CD57, 2CCF5, 2CD99, 2CCE7, 2CCE9, 2CD7B, 2CEBE, 2CE99","status":"derivada del contorno CAD"},{"label":"Extensión local Y","value":0.45,"unit":"m","source":"2CCDD, 2CD57, 2CCF5, 2CD99, 2CCE7, 2CCE9, 2CD7B, 2CEBE, 2CE99","status":"derivada del contorno CAD"},{"label":"Cota inferior relativa adoptada","value":-0.6,"unit":"m","source":"ZD1 / DZ-1","status":"documentada"},{"label":"Cota superior relativa adoptada","value":0.2,"unit":"m","source":"ZD1 / DZ-1","status":"documentada / separación por material"}],"geometry":[{"label":"Extensión de la malla en X","value":0.5070979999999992,"unit":"m","source":"Geometría releída del IFC; datum absoluto de proceso provisional","status":"derivado"},{"label":"Extensión de la malla en Y","value":0.5070980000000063,"unit":"m","source":"Geometría releída del IFC; datum absoluto de proceso provisional","status":"derivado"},{"label":"Extensión de la malla en Z","value":0.8,"unit":"m","source":"Geometría releída del IFC; datum absoluto de proceso provisional","status":"derivado"},{"label":"Cota inferior de visualización","value":285.5,"unit":"m","source":"Geometría releída del IFC; datum absoluto de proceso provisional","status":"derivado"},{"label":"Cota superior de visualización","value":286.3,"unit":"m","source":"Geometría releída del IFC; datum absoluto de proceso provisional","status":"derivado"}]} | {"documentId":"LHD2609-JG00100-20260904","title":"Cimentaciones de equipos y pedestales del fabricante · revisión recibida 04/09/2026","date":"2026-09-04","sheet":"ZD1 / DZ-1","fileName":"LHD2609-JG00100_20260904.dwg","revisionCaveat":"Fecha de revisión tomada del nombre recibido; cajetines internos mantienen 02/07/2026 y algunos textos de plantilla.","sourceFileSha256":"b42eb027b7bc0b14c38d1d13514f4899b58a732aa8d0ba2ccf10fa2fc3192890"} | provisional | [] | {"Cota inferior relativa (m)":-0.6,"Cota superior relativa (m)":0.2,"Cero absoluto de visualización (m)":286.1,"Estado del cero absoluto":"Provisional","Criterio":"Las cotas relativas proceden del dibujo; la equivalencia absoluta no está confirmada."} | {"boundingBoxM":{"min":[61.987012,50.230214,0.5],"max":[62.49411,50.737312,1.3]},"extentsM":[0.507098,0.507098,0.8],"meshSurfaceM2":1.844999,"meshVolumeM3":0.162,"closedSolid":true,"basis":"Magnitudes de las mallas representadas, no cantidades certificadas de obra, compra o fabricación. Las partes pueden compartir superficies; no se suman como un despiece de materiales."} | {"profileId":"concrete_ha30","name":"Hormigón HA-30","materialName":"Hormigón HA-30","physicalMaterialStatus":"documentado","physicalMaterialSource":"Nota general de pedestales 2CED5","appearanceStatus":"criterio_visual","appearanceBasis":"Interpretación visual del material documental; el acabado, tono y parámetros PBR no son una especificación contractual.","note":"La apariencia gráfica no modifica ni confirma la especificación física del material."} | {"elementId":"found_0904_11bb0e88c2ca44","ifcGuid":"3aiW7Xl6XUsP1oGa43PGoA","ifcClass":"IfcFooting","buildingId":"process_plant","buildingName":"Zona de separación de aire","sourceDocumentId":"LHD2609-JG00100-20260904","sourceRepresentationKind":"foundation"} | {"layerId":"foundations","layerName":"Cimentaciones","role":"Cimentación industrial","basis":"Clasificación por función del elemento; no modifica las especificaciones documentales."} | {"profileId":"concrete_ha30","name":"Hormigón HA-30","status":"criterio_visual","basis":"Interpretación visual del material documental; el acabado, tono y parámetros PBR no son una especificación contractual.","physicalMaterialUnchanged":true} | 0.162 | Hormigón HA-30 | Hormigón HA-30 | found_0904_11bb0e88c2ca44 | Nota general de pedestales 2CED5 | documentado | concrete_ha30 | [0.658824,0.658824,0.623529] | 0.94 | Zona de separación de aire; BIM · Cimentaciones | 0.507098 | 0.507098 | 0.8 | 285.5 | 286.3 | SUP-C28 | [] | ["C28"] | ZD1 / DZ-1 | ["2CCDD","2CD57","2CCF5","2CD99","2CCE7","2CCE9","2CD7B","2CEBE","2CE99"] | SUP-C28/Cimentación de soporte de tuberías C28 · pedestal de hormigón | foundation | Geometría de fabricante; implantación absoluta provisional |  | Cimentaciones de equipos y pedestales del fabricante · revisión recibida 04/09/2026 | 2CCDD, 2CD57, 2CCF5, 2CD99, 2CCE7, 2CCE9, 2CD7B, 2CEBE, 2CE99 | -0.6 | 0.2 | 0.2025 | Cotas relativas del dibujo. La equivalencia con un datum absoluto está pendiente. | Z del modelo = cota relativa + 1,10 m. Correspondencia provisional con 286,10 m; no es cota de obra confirmada. | Contornos y sección documentados por el fabricante | 0.45 | 0.45 | Material: Hormigón HA-30
Cimentación de soporte de tuberías C29 · cuerpo de hormigón | Parcela industrial Jinhong | Cimentación industrial | Cimentaciones de equipos y pedestales del fabricante · revisión recibida 04/09/2026 | 1.12689 | 1.12689 | 0.4 | 3.6 | 0.4 | process_plant | Zona de separación de aire | {"name":"Hormigón HA-30","status":"documentado","source":"Nota general de pedestales 2CED5"} | {"documented":[{"label":"Extensión local X","value":1.0,"unit":"m","source":"2CCDE, 2CD61, 2CCF6, 2CD9A, 2CCF1, 2CCEC, 2CD85, 2CEBF, 2CE9A","status":"derivada del contorno CAD"},{"label":"Extensión local Y","value":1.0,"unit":"m","source":"2CCDE, 2CD61, 2CCF6, 2CD9A, 2CCF1, 2CCEC, 2CD85, 2CEBF, 2CE9A","status":"derivada del contorno CAD"},{"label":"Cota inferior relativa adoptada","value":-1.0,"unit":"m","source":"ZD1 / DZ-2","status":"documentada"},{"label":"Cota superior relativa adoptada","value":-0.6,"unit":"m","source":"ZD1 / DZ-2","status":"documentada / separación por material"}],"geometry":[{"label":"Extensión de la malla en X","value":1.1268850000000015,"unit":"m","source":"Geometría releída del IFC; datum absoluto de proceso provisional","status":"derivado"},{"label":"Extensión de la malla en Y","value":1.1268850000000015,"unit":"m","source":"Geometría releída del IFC; datum absoluto de proceso provisional","status":"derivado"},{"label":"Extensión de la malla en Z","value":0.4,"unit":"m","source":"Geometría releída del IFC; datum absoluto de proceso provisional","status":"derivado"},{"label":"Cota inferior de visualización","value":285.1,"unit":"m","source":"Geometría releída del IFC; datum absoluto de proceso provisional","status":"derivado"},{"label":"Cota superior de visualización","value":285.5,"unit":"m","source":"Geometría releída del IFC; datum absoluto de proceso provisional","status":"derivado"}]} | {"documentId":"LHD2609-JG00100-20260904","title":"Cimentaciones de equipos y pedestales del fabricante · revisión recibida 04/09/2026","date":"2026-09-04","sheet":"ZD1 / DZ-2","fileName":"LHD2609-JG00100_20260904.dwg","revisionCaveat":"Fecha de revisión tomada del nombre recibido; cajetines internos mantienen 02/07/2026 y algunos textos de plantilla.","sourceFileSha256":"b42eb027b7bc0b14c38d1d13514f4899b58a732aa8d0ba2ccf10fa2fc3192890"} | provisional | [] | {"Cota inferior relativa (m)":-1.0,"Cota superior relativa (m)":-0.6,"Cero absoluto de visualización (m)":286.1,"Estado del cero absoluto":"Provisional","Criterio":"Las cotas relativas proceden del dibujo; la equivalencia absoluta no está confirmada."} | {"boundingBoxM":{"min":[42.810586,48.703678,0.1],"max":[43.937471,49.830563,0.5]},"extentsM":[1.126885,1.126885,0.4],"meshSurfaceM2":3.600001,"meshVolumeM3":0.4,"closedSolid":true,"basis":"Magnitudes de las mallas representadas, no cantidades certificadas de obra, compra o fabricación. Las partes pueden compartir superficies; no se suman como un despiece de materiales."} | {"profileId":"concrete_ha30","name":"Hormigón HA-30","materialName":"Hormigón HA-30","physicalMaterialStatus":"documentado","physicalMaterialSource":"Nota general de pedestales 2CED5","appearanceStatus":"criterio_visual","appearanceBasis":"Interpretación visual del material documental; el acabado, tono y parámetros PBR no son una especificación contractual.","note":"La apariencia gráfica no modifica ni confirma la especificación física del material."} | {"elementId":"found_0904_bbf3c641c36e11","ifcGuid":"0I77ab$tTVmPK6P0WmowaM","ifcClass":"IfcFooting","buildingId":"process_plant","buildingName":"Zona de separación de aire","sourceDocumentId":"LHD2609-JG00100-20260904","sourceRepresentationKind":"foundation"} | {"layerId":"foundations","layerName":"Cimentaciones","role":"Cimentación industrial","basis":"Clasificación por función del elemento; no modifica las especificaciones documentales."} | {"profileId":"concrete_ha30","name":"Hormigón HA-30","status":"criterio_visual","basis":"Interpretación visual del material documental; el acabado, tono y parámetros PBR no son una especificación contractual.","physicalMaterialUnchanged":true} | 0.4 | Hormigón HA-30 | Hormigón HA-30 | found_0904_bbf3c641c36e11 | Nota general de pedestales 2CED5 | documentado | concrete_ha30 | [0.658824,0.658824,0.623529] | 0.94 | Zona de separación de aire; BIM · Cimentaciones | 1.12689 | 1.12689 | 0.4 | 285.1 | 285.5 | SUP-C29 | [] | ["C29"] | ZD1 / DZ-2 | ["2CCDE","2CD61","2CCF6","2CD9A","2CCF1","2CCEC","2CD85","2CEBF","2CE9A"] | SUP-C29/Cimentación de soporte de tuberías C29 · cuerpo de hormigón | foundation | Geometría de fabricante; implantación absoluta provisional |  | Cimentaciones de equipos y pedestales del fabricante · revisión recibida 04/09/2026 | 2CCDE, 2CD61, 2CCF6, 2CD9A, 2CCF1, 2CCEC, 2CD85, 2CEBF, 2CE9A | -1 | -0.6 | 1 | Cotas relativas del dibujo. La equivalencia con un datum absoluto está pendiente. | Z del modelo = cota relativa + 1,10 m. Correspondencia provisional con 286,10 m; no es cota de obra confirmada. | Contornos y sección documentados por el fabricante | 1 | 1 | Material: Hormigón HA-30
Cimentación de soporte de tuberías C29 · pedestal de hormigón | Parcela industrial Jinhong | Cimentación industrial | Cimentaciones de equipos y pedestales del fabricante · revisión recibida 04/09/2026 | 0.563442 | 0.563443 | 0.8 | 2.1 | 0.2 | process_plant | Zona de separación de aire | {"name":"Hormigón HA-30","status":"documentado","source":"Nota general de pedestales 2CED5"} | {"documented":[{"label":"Extensión local X","value":0.5,"unit":"m","source":"2CCDE, 2CD61, 2CCF6, 2CD9A, 2CCF1, 2CCEC, 2CD85, 2CEBF, 2CE9A","status":"derivada del contorno CAD"},{"label":"Extensión local Y","value":0.5,"unit":"m","source":"2CCDE, 2CD61, 2CCF6, 2CD9A, 2CCF1, 2CCEC, 2CD85, 2CEBF, 2CE9A","status":"derivada del contorno CAD"},{"label":"Cota inferior relativa adoptada","value":-0.6,"unit":"m","source":"ZD1 / DZ-2","status":"documentada"},{"label":"Cota superior relativa adoptada","value":0.2,"unit":"m","source":"ZD1 / DZ-2","status":"documentada / separación por material"}],"geometry":[{"label":"Extensión de la malla en X","value":0.5634419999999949,"unit":"m","source":"Geometría releída del IFC; datum absoluto de proceso provisional","status":"derivado"},{"label":"Extensión de la malla en Y","value":0.5634429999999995,"unit":"m","source":"Geometría releída del IFC; datum absoluto de proceso provisional","status":"derivado"},{"label":"Extensión de la malla en Z","value":0.8,"unit":"m","source":"Geometría releída del IFC; datum absoluto de proceso provisional","status":"derivado"},{"label":"Cota inferior de visualización","value":285.5,"unit":"m","source":"Geometría releída del IFC; datum absoluto de proceso provisional","status":"derivado"},{"label":"Cota superior de visualización","value":286.3,"unit":"m","source":"Geometría releída del IFC; datum absoluto de proceso provisional","status":"derivado"}]} | {"documentId":"LHD2609-JG00100-20260904","title":"Cimentaciones de equipos y pedestales del fabricante · revisión recibida 04/09/2026","date":"2026-09-04","sheet":"ZD1 / DZ-2","fileName":"LHD2609-JG00100_20260904.dwg","revisionCaveat":"Fecha de revisión tomada del nombre recibido; cajetines internos mantienen 02/07/2026 y algunos textos de plantilla.","sourceFileSha256":"b42eb027b7bc0b14c38d1d13514f4899b58a732aa8d0ba2ccf10fa2fc3192890"} | provisional | [] | {"Cota inferior relativa (m)":-0.6,"Cota superior relativa (m)":0.2,"Cero absoluto de visualización (m)":286.1,"Estado del cero absoluto":"Provisional","Criterio":"Las cotas relativas proceden del dibujo; la equivalencia absoluta no está confirmada."} | {"boundingBoxM":{"min":[43.092308,48.985399,0.5],"max":[43.65575,49.548842,1.3]},"extentsM":[0.563442,0.563443,0.8],"meshSurfaceM2":2.1,"meshVolumeM3":0.2,"closedSolid":true,"basis":"Magnitudes de las mallas representadas, no cantidades certificadas de obra, compra o fabricación. Las partes pueden compartir superficies; no se suman como un despiece de materiales."} | {"profileId":"concrete_ha30","name":"Hormigón HA-30","materialName":"Hormigón HA-30","physicalMaterialStatus":"documentado","physicalMaterialSource":"Nota general de pedestales 2CED5","appearanceStatus":"criterio_visual","appearanceBasis":"Interpretación visual del material documental; el acabado, tono y parámetros PBR no son una especificación contractual.","note":"La apariencia gráfica no modifica ni confirma la especificación física del material."} | {"elementId":"found_0904_602b7a8715f7bf","ifcGuid":"3dZK$UDunUIvKIxoT6FQRt","ifcClass":"IfcFooting","buildingId":"process_plant","buildingName":"Zona de separación de aire","sourceDocumentId":"LHD2609-JG00100-20260904","sourceRepresentationKind":"foundation"} | {"layerId":"foundations","layerName":"Cimentaciones","role":"Cimentación industrial","basis":"Clasificación por función del elemento; no modifica las especificaciones documentales."} | {"profileId":"concrete_ha30","name":"Hormigón HA-30","status":"criterio_visual","basis":"Interpretación visual del material documental; el acabado, tono y parámetros PBR no son una especificación contractual.","physicalMaterialUnchanged":true} | 0.2 | Hormigón HA-30 | Hormigón HA-30 | found_0904_602b7a8715f7bf | Nota general de pedestales 2CED5 | documentado | concrete_ha30 | [0.658824,0.658824,0.623529] | 0.94 | Zona de separación de aire; BIM · Cimentaciones | 0.563442 | 0.563443 | 0.8 | 285.5 | 286.3 | SUP-C29 | [] | ["C29"] | ZD1 / DZ-2 | ["2CCDE","2CD61","2CCF6","2CD9A","2CCF1","2CCEC","2CD85","2CEBF","2CE9A"] | SUP-C29/Cimentación de soporte de tuberías C29 · pedestal de hormigón | foundation | Geometría de fabricante; implantación absoluta provisional |  | Cimentaciones de equipos y pedestales del fabricante · revisión recibida 04/09/2026 | 2CCDE, 2CD61, 2CCF6, 2CD9A, 2CCF1, 2CCEC, 2CD85, 2CEBF, 2CE9A | -0.6 | 0.2 | 0.25 | Cotas relativas del dibujo. La equivalencia con un datum absoluto está pendiente. | Z del modelo = cota relativa + 1,10 m. Correspondencia provisional con 286,10 m; no es cota de obra confirmada. | Contornos y sección documentados por el fabricante | 0.5 | 0.5 | Material: Hormigón HA-30
Cimentación de soporte de tuberías C30 · cuerpo de hormigón | Parcela industrial Jinhong | Cimentación industrial | Cimentaciones de equipos y pedestales del fabricante · revisión recibida 04/09/2026 | 1.12689 | 1.12688 | 0.4 | 3.6 | 0.4 | process_plant | Zona de separación de aire | {"name":"Hormigón HA-30","status":"documentado","source":"Nota general de pedestales 2CED5"} | {"documented":[{"label":"Extensión local X","value":1.0,"unit":"m","source":"2CCDF, 2CD62, 2CCF7, 2CD9B, 2CCEF, 2CCF0, 2CD86, 2CEC0, 2CE9B","status":"derivada del contorno CAD"},{"label":"Extensión local Y","value":1.0,"unit":"m","source":"2CCDF, 2CD62, 2CCF7, 2CD9B, 2CCEF, 2CCF0, 2CD86, 2CEC0, 2CE9B","status":"derivada del contorno CAD"},{"label":"Cota inferior relativa adoptada","value":-1.0,"unit":"m","source":"ZD1 / DZ-2","status":"interpretación con conflicto conservado"},{"label":"Cota superior relativa adoptada","value":-0.6,"unit":"m","source":"ZD1 / DZ-2","status":"documentada / separación por material"}],"geometry":[{"label":"Extensión de la malla en X","value":1.1268850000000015,"unit":"m","source":"Geometría releída del IFC; datum absoluto de proceso provisional","status":"derivado"},{"label":"Extensión de la malla en Y","value":1.126884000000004,"unit":"m","source":"Geometría releída del IFC; datum absoluto de proceso provisional","status":"derivado"},{"label":"Extensión de la malla en Z","value":0.4,"unit":"m","source":"Geometría releída del IFC; datum absoluto de proceso provisional","status":"derivado"},{"label":"Cota inferior de visualización","value":285.1,"unit":"m","source":"Geometría releída del IFC; datum absoluto de proceso provisional","status":"derivado"},{"label":"Cota superior de visualización","value":285.5,"unit":"m","source":"Geometría releída del IFC; datum absoluto de proceso provisional","status":"derivado"}]} | {"documentId":"LHD2609-JG00100-20260904","title":"Cimentaciones de equipos y pedestales del fabricante · revisión recibida 04/09/2026","date":"2026-09-04","sheet":"ZD1 / DZ-2","fileName":"LHD2609-JG00100_20260904.dwg","revisionCaveat":"Fecha de revisión tomada del nombre recibido; cajetines internos mantienen 02/07/2026 y algunos textos de plantilla.","sourceFileSha256":"b42eb027b7bc0b14c38d1d13514f4899b58a732aa8d0ba2ccf10fa2fc3192890"} | provisional | ["Identificador original HA-30 en columna de posición; C30 se infiere por secuencia. Se conserva el original y no se interpreta como material."] | {"Cota inferior relativa (m)":-1.0,"Cota superior relativa (m)":-0.6,"Cero absoluto de visualización (m)":286.1,"Estado del cero absoluto":"Provisional","Criterio":"Las cotas relativas proceden del dibujo; la equivalencia absoluta no está confirmada."} | {"boundingBoxM":{"min":[42.061465,43.254934,0.1],"max":[43.18835,44.381818,0.5]},"extentsM":[1.126885,1.126884,0.4],"meshSurfaceM2":3.599999,"meshVolumeM3":0.4,"closedSolid":true,"basis":"Magnitudes de las mallas representadas, no cantidades certificadas de obra, compra o fabricación. Las partes pueden compartir superficies; no se suman como un despiece de materiales."} | {"profileId":"concrete_ha30","name":"Hormigón HA-30","materialName":"Hormigón HA-30","physicalMaterialStatus":"documentado","physicalMaterialSource":"Nota general de pedestales 2CED5","appearanceStatus":"criterio_visual","appearanceBasis":"Interpretación visual del material documental; el acabado, tono y parámetros PBR no son una especificación contractual.","note":"La apariencia gráfica no modifica ni confirma la especificación física del material."} | {"elementId":"found_0904_58a0b341783fbe","ifcGuid":"1fMcOwWgvQrQ7Fb10Y$ZNO","ifcClass":"IfcFooting","buildingId":"process_plant","buildingName":"Zona de separación de aire","sourceDocumentId":"LHD2609-JG00100-20260904","sourceRepresentationKind":"foundation"} | {"layerId":"foundations","layerName":"Cimentaciones","role":"Cimentación industrial","basis":"Clasificación por función del elemento; no modifica las especificaciones documentales."} | {"profileId":"concrete_ha30","name":"Hormigón HA-30","status":"criterio_visual","basis":"Interpretación visual del material documental; el acabado, tono y parámetros PBR no son una especificación contractual.","physicalMaterialUnchanged":true} | 0.4 | Hormigón HA-30 | Hormigón HA-30 | found_0904_58a0b341783fbe | Nota general de pedestales 2CED5 | documentado | concrete_ha30 | [0.658824,0.658824,0.623529] | 0.94 | Zona de separación de aire; BIM · Cimentaciones | 1.12689 | 1.12688 | 0.4 | 285.1 | 285.5 | SUP-C30 | [] | ["C30"] | ZD1 / DZ-2 | ["2CCDF","2CD62","2CCF7","2CD9B","2CCEF","2CCF0","2CD86","2CEC0","2CE9B"] | SUP-C30/Cimentación de soporte de tuberías C30 · cuerpo de hormigón | foundation | Geometría de fabricante; implantación absoluta provisional |  | Cimentaciones de equipos y pedestales del fabricante · revisión recibida 04/09/2026 | 2CCDF, 2CD62, 2CCF7, 2CD9B, 2CCEF, 2CCF0, 2CD86, 2CEC0, 2CE9B | -1 | -0.6 | 1 | Cotas relativas del dibujo. La equivalencia con un datum absoluto está pendiente. | Z del modelo = cota relativa + 1,10 m. Correspondencia provisional con 286,10 m; no es cota de obra confirmada. | Sección y contornos del fabricante; incidencias conservadas | 1 | 1 | Identificador original HA-30 en columna de posición; C30 se infiere por secuencia. Se conserva el original y no se interpreta como material. | Material: Hormigón HA-30
Cimentación de soporte de tuberías C30 · pedestal de hormigón | Parcela industrial Jinhong | Cimentación industrial | Cimentaciones de equipos y pedestales del fabricante · revisión recibida 04/09/2026 | 0.563442 | 0.563442 | 0.8 | 2.1 | 0.2 | process_plant | Zona de separación de aire | {"name":"Hormigón HA-30","status":"documentado","source":"Nota general de pedestales 2CED5"} | {"documented":[{"label":"Extensión local X","value":0.5,"unit":"m","source":"2CCDF, 2CD62, 2CCF7, 2CD9B, 2CCEF, 2CCF0, 2CD86, 2CEC0, 2CE9B","status":"derivada del contorno CAD"},{"label":"Extensión local Y","value":0.5,"unit":"m","source":"2CCDF, 2CD62, 2CCF7, 2CD9B, 2CCEF, 2CCF0, 2CD86, 2CEC0, 2CE9B","status":"derivada del contorno CAD"},{"label":"Cota inferior relativa adoptada","value":-0.6,"unit":"m","source":"ZD1 / DZ-2","status":"interpretación con conflicto conservado"},{"label":"Cota superior relativa adoptada","value":0.2,"unit":"m","source":"ZD1 / DZ-2","status":"documentada / separación por material"}],"geometry":[{"label":"Extensión de la malla en X","value":0.5634419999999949,"unit":"m","source":"Geometría releída del IFC; datum absoluto de proceso provisional","status":"derivado"},{"label":"Extensión de la malla en Y","value":0.5634419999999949,"unit":"m","source":"Geometría releída del IFC; datum absoluto de proceso provisional","status":"derivado"},{"label":"Extensión de la malla en Z","value":0.8,"unit":"m","source":"Geometría releída del IFC; datum absoluto de proceso provisional","status":"derivado"},{"label":"Cota inferior de visualización","value":285.5,"unit":"m","source":"Geometría releída del IFC; datum absoluto de proceso provisional","status":"derivado"},{"label":"Cota superior de visualización","value":286.3,"unit":"m","source":"Geometría releída del IFC; datum absoluto de proceso provisional","status":"derivado"}]} | {"documentId":"LHD2609-JG00100-20260904","title":"Cimentaciones de equipos y pedestales del fabricante · revisión recibida 04/09/2026","date":"2026-09-04","sheet":"ZD1 / DZ-2","fileName":"LHD2609-JG00100_20260904.dwg","revisionCaveat":"Fecha de revisión tomada del nombre recibido; cajetines internos mantienen 02/07/2026 y algunos textos de plantilla.","sourceFileSha256":"b42eb027b7bc0b14c38d1d13514f4899b58a732aa8d0ba2ccf10fa2fc3192890"} | provisional | ["Identificador original HA-30 en columna de posición; C30 se infiere por secuencia. Se conserva el original y no se interpreta como material."] | {"Cota inferior relativa (m)":-0.6,"Cota superior relativa (m)":0.2,"Cero absoluto de visualización (m)":286.1,"Estado del cero absoluto":"Provisional","Criterio":"Las cotas relativas proceden del dibujo; la equivalencia absoluta no está confirmada."} | {"boundingBoxM":{"min":[42.343186,43.536655,0.5],"max":[42.906628,44.100097,1.3]},"extentsM":[0.563442,0.563442,0.8],"meshSurfaceM2":2.099998,"meshVolumeM3":0.2,"closedSolid":true,"basis":"Magnitudes de las mallas representadas, no cantidades certificadas de obra, compra o fabricación. Las partes pueden compartir superficies; no se suman como un despiece de materiales."} | {"profileId":"concrete_ha30","name":"Hormigón HA-30","materialName":"Hormigón HA-30","physicalMaterialStatus":"documentado","physicalMaterialSource":"Nota general de pedestales 2CED5","appearanceStatus":"criterio_visual","appearanceBasis":"Interpretación visual del material documental; el acabado, tono y parámetros PBR no son una especificación contractual.","note":"La apariencia gráfica no modifica ni confirma la especificación física del material."} | {"elementId":"found_0904_a92d8636916341","ifcGuid":"3O3FfbkebJ8xXWxGk66XuN","ifcClass":"IfcFooting","buildingId":"process_plant","buildingName":"Zona de separación de aire","sourceDocumentId":"LHD2609-JG00100-20260904","sourceRepresentationKind":"foundation"} | {"layerId":"foundations","layerName":"Cimentaciones","role":"Cimentación industrial","basis":"Clasificación por función del elemento; no modifica las especificaciones documentales."} | {"profileId":"concrete_ha30","name":"Hormigón HA-30","status":"criterio_visual","basis":"Interpretación visual del material documental; el acabado, tono y parámetros PBR no son una especificación contractual.","physicalMaterialUnchanged":true} | 0.2 | Hormigón HA-30 | Hormigón HA-30 | found_0904_a92d8636916341 | Nota general de pedestales 2CED5 | documentado | concrete_ha30 | [0.658824,0.658824,0.623529] | 0.94 | Zona de separación de aire; BIM · Cimentaciones | 0.563442 | 0.563442 | 0.8 | 285.5 | 286.3 | SUP-C30 | [] | ["C30"] | ZD1 / DZ-2 | ["2CCDF","2CD62","2CCF7","2CD9B","2CCEF","2CCF0","2CD86","2CEC0","2CE9B"] | SUP-C30/Cimentación de soporte de tuberías C30 · pedestal de hormigón | foundation | Geometría de fabricante; implantación absoluta provisional |  | Cimentaciones de equipos y pedestales del fabricante · revisión recibida 04/09/2026 | 2CCDF, 2CD62, 2CCF7, 2CD9B, 2CCEF, 2CCF0, 2CD86, 2CEC0, 2CE9B | -0.6 | 0.2 | 0.25 | Cotas relativas del dibujo. La equivalencia con un datum absoluto está pendiente. | Z del modelo = cota relativa + 1,10 m. Correspondencia provisional con 286,10 m; no es cota de obra confirmada. | Sección y contornos del fabricante; incidencias conservadas | 0.5 | 0.5 | Identificador original HA-30 en columna de posición; C30 se infiere por secuencia. Se conserva el original y no se interpreta como material. | Material: Hormigón HA-30
Cimentación de soporte de tuberías C31 · cuerpo de hormigón | Parcela industrial Jinhong | Cimentación industrial | Cimentaciones de equipos y pedestales del fabricante · revisión recibida 04/09/2026 | 1.12689 | 1.12689 | 0.4 | 3.6 | 0.4 | process_plant | Zona de separación de aire | {"name":"Hormigón HA-30","status":"documentado","source":"Nota general de pedestales 2CED5"} | {"documented":[{"label":"Extensión local X","value":1.0,"unit":"m","source":"2CCE0, 2CD63, 2CCF8, 2CD9C, 2CCED, 2CCEE, 2CD87, 2CEC1, 2CE9C","status":"derivada del contorno CAD"},{"label":"Extensión local Y","value":1.0,"unit":"m","source":"2CCE0, 2CD63, 2CCF8, 2CD9C, 2CCED, 2CCEE, 2CD87, 2CEC1, 2CE9C","status":"derivada del contorno CAD"},{"label":"Cota inferior relativa adoptada","value":-1.0,"unit":"m","source":"ZD1 / DZ-2","status":"documentada"},{"label":"Cota superior relativa adoptada","value":-0.6,"unit":"m","source":"ZD1 / DZ-2","status":"documentada / separación por material"}],"geometry":[{"label":"Extensión de la malla en X","value":1.1268850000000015,"unit":"m","source":"Geometría releída del IFC; datum absoluto de proceso provisional","status":"derivado"},{"label":"Extensión de la malla en Y","value":1.1268850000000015,"unit":"m","source":"Geometría releída del IFC; datum absoluto de proceso provisional","status":"derivado"},{"label":"Extensión de la malla en Z","value":0.4,"unit":"m","source":"Geometría releída del IFC; datum absoluto de proceso provisional","status":"derivado"},{"label":"Cota inferior de visualización","value":285.1,"unit":"m","source":"Geometría releída del IFC; datum absoluto de proceso provisional","status":"derivado"},{"label":"Cota superior de visualización","value":285.5,"unit":"m","source":"Geometría releída del IFC; datum absoluto de proceso provisional","status":"derivado"}]} | {"documentId":"LHD2609-JG00100-20260904","title":"Cimentaciones de equipos y pedestales del fabricante · revisión recibida 04/09/2026","date":"2026-09-04","sheet":"ZD1 / DZ-2","fileName":"LHD2609-JG00100_20260904.dwg","revisionCaveat":"Fecha de revisión tomada del nombre recibido; cajetines internos mantienen 02/07/2026 y algunos textos de plantilla.","sourceFileSha256":"b42eb027b7bc0b14c38d1d13514f4899b58a732aa8d0ba2ccf10fa2fc3192890"} | provisional | [] | {"Cota inferior relativa (m)":-1.0,"Cota superior relativa (m)":-0.6,"Cero absoluto de visualización (m)":286.1,"Estado del cero absoluto":"Provisional","Criterio":"Las cotas relativas proceden del dibujo; la equivalencia absoluta no está confirmada."} | {"boundingBoxM":{"min":[46.749794,47.253629,0.1],"max":[47.876679,48.380514,0.5]},"extentsM":[1.126885,1.126885,0.4],"meshSurfaceM2":3.600001,"meshVolumeM3":0.4,"closedSolid":true,"basis":"Magnitudes de las mallas representadas, no cantidades certificadas de obra, compra o fabricación. Las partes pueden compartir superficies; no se suman como un despiece de materiales."} | {"profileId":"concrete_ha30","name":"Hormigón HA-30","materialName":"Hormigón HA-30","physicalMaterialStatus":"documentado","physicalMaterialSource":"Nota general de pedestales 2CED5","appearanceStatus":"criterio_visual","appearanceBasis":"Interpretación visual del material documental; el acabado, tono y parámetros PBR no son una especificación contractual.","note":"La apariencia gráfica no modifica ni confirma la especificación física del material."} | {"elementId":"found_0904_baa22d17c46960","ifcGuid":"0OCtc1fu5NGggynwqxagkW","ifcClass":"IfcFooting","buildingId":"process_plant","buildingName":"Zona de separación de aire","sourceDocumentId":"LHD2609-JG00100-20260904","sourceRepresentationKind":"foundation"} | {"layerId":"foundations","layerName":"Cimentaciones","role":"Cimentación industrial","basis":"Clasificación por función del elemento; no modifica las especificaciones documentales."} | {"profileId":"concrete_ha30","name":"Hormigón HA-30","status":"criterio_visual","basis":"Interpretación visual del material documental; el acabado, tono y parámetros PBR no son una especificación contractual.","physicalMaterialUnchanged":true} | 0.4 | Hormigón HA-30 | Hormigón HA-30 | found_0904_baa22d17c46960 | Nota general de pedestales 2CED5 | documentado | concrete_ha30 | [0.658824,0.658824,0.623529] | 0.94 | Zona de separación de aire; BIM · Cimentaciones | 1.12689 | 1.12689 | 0.4 | 285.1 | 285.5 | SUP-C31 | [] | ["C31"] | ZD1 / DZ-2 | ["2CCE0","2CD63","2CCF8","2CD9C","2CCED","2CCEE","2CD87","2CEC1","2CE9C"] | SUP-C31/Cimentación de soporte de tuberías C31 · cuerpo de hormigón | foundation | Geometría de fabricante; implantación absoluta provisional |  | Cimentaciones de equipos y pedestales del fabricante · revisión recibida 04/09/2026 | 2CCE0, 2CD63, 2CCF8, 2CD9C, 2CCED, 2CCEE, 2CD87, 2CEC1, 2CE9C | -1 | -0.6 | 1 | Cotas relativas del dibujo. La equivalencia con un datum absoluto está pendiente. | Z del modelo = cota relativa + 1,10 m. Correspondencia provisional con 286,10 m; no es cota de obra confirmada. | Contornos y sección documentados por el fabricante | 1 | 1 | Material: Hormigón HA-30
Cimentación de soporte de tuberías C31 · pedestal de hormigón | Parcela industrial Jinhong | Cimentación industrial | Cimentaciones de equipos y pedestales del fabricante · revisión recibida 04/09/2026 | 0.563443 | 0.563443 | 0.8 | 2.1 | 0.2 | process_plant | Zona de separación de aire | {"name":"Hormigón HA-30","status":"documentado","source":"Nota general de pedestales 2CED5"} | {"documented":[{"label":"Extensión local X","value":0.5,"unit":"m","source":"2CCE0, 2CD63, 2CCF8, 2CD9C, 2CCED, 2CCEE, 2CD87, 2CEC1, 2CE9C","status":"derivada del contorno CAD"},{"label":"Extensión local Y","value":0.5,"unit":"m","source":"2CCE0, 2CD63, 2CCF8, 2CD9C, 2CCED, 2CCEE, 2CD87, 2CEC1, 2CE9C","status":"derivada del contorno CAD"},{"label":"Cota inferior relativa adoptada","value":-0.6,"unit":"m","source":"ZD1 / DZ-2","status":"documentada"},{"label":"Cota superior relativa adoptada","value":0.2,"unit":"m","source":"ZD1 / DZ-2","status":"documentada / separación por material"}],"geometry":[{"label":"Extensión de la malla en X","value":0.5634429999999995,"unit":"m","source":"Geometría releída del IFC; datum absoluto de proceso provisional","status":"derivado"},{"label":"Extensión de la malla en Y","value":0.5634429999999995,"unit":"m","source":"Geometría releída del IFC; datum absoluto de proceso provisional","status":"derivado"},{"label":"Extensión de la malla en Z","value":0.8,"unit":"m","source":"Geometría releída del IFC; datum absoluto de proceso provisional","status":"derivado"},{"label":"Cota inferior de visualización","value":285.5,"unit":"m","source":"Geometría releída del IFC; datum absoluto de proceso provisional","status":"derivado"},{"label":"Cota superior de visualización","value":286.3,"unit":"m","source":"Geometría releída del IFC; datum absoluto de proceso provisional","status":"derivado"}]} | {"documentId":"LHD2609-JG00100-20260904","title":"Cimentaciones de equipos y pedestales del fabricante · revisión recibida 04/09/2026","date":"2026-09-04","sheet":"ZD1 / DZ-2","fileName":"LHD2609-JG00100_20260904.dwg","revisionCaveat":"Fecha de revisión tomada del nombre recibido; cajetines internos mantienen 02/07/2026 y algunos textos de plantilla.","sourceFileSha256":"b42eb027b7bc0b14c38d1d13514f4899b58a732aa8d0ba2ccf10fa2fc3192890"} | provisional | [] | {"Cota inferior relativa (m)":-0.6,"Cota superior relativa (m)":0.2,"Cero absoluto de visualización (m)":286.1,"Estado del cero absoluto":"Provisional","Criterio":"Las cotas relativas proceden del dibujo; la equivalencia absoluta no está confirmada."} | {"boundingBoxM":{"min":[47.031515,47.53535,0.5],"max":[47.594958,48.098793,1.3]},"extentsM":[0.563443,0.563443,0.8],"meshSurfaceM2":2.100003,"meshVolumeM3":0.2,"closedSolid":true,"basis":"Magnitudes de las mallas representadas, no cantidades certificadas de obra, compra o fabricación. Las partes pueden compartir superficies; no se suman como un despiece de materiales."} | {"profileId":"concrete_ha30","name":"Hormigón HA-30","materialName":"Hormigón HA-30","physicalMaterialStatus":"documentado","physicalMaterialSource":"Nota general de pedestales 2CED5","appearanceStatus":"criterio_visual","appearanceBasis":"Interpretación visual del material documental; el acabado, tono y parámetros PBR no son una especificación contractual.","note":"La apariencia gráfica no modifica ni confirma la especificación física del material."} | {"elementId":"found_0904_f69088cc5de9dc","ifcGuid":"3qzJ$hRQ5RXP88c$X6Vrqn","ifcClass":"IfcFooting","buildingId":"process_plant","buildingName":"Zona de separación de aire","sourceDocumentId":"LHD2609-JG00100-20260904","sourceRepresentationKind":"foundation"} | {"layerId":"foundations","layerName":"Cimentaciones","role":"Cimentación industrial","basis":"Clasificación por función del elemento; no modifica las especificaciones documentales."} | {"profileId":"concrete_ha30","name":"Hormigón HA-30","status":"criterio_visual","basis":"Interpretación visual del material documental; el acabado, tono y parámetros PBR no son una especificación contractual.","physicalMaterialUnchanged":true} | 0.2 | Hormigón HA-30 | Hormigón HA-30 | found_0904_f69088cc5de9dc | Nota general de pedestales 2CED5 | documentado | concrete_ha30 | [0.658824,0.658824,0.623529] | 0.94 | Zona de separación de aire; BIM · Cimentaciones | 0.563443 | 0.563443 | 0.8 | 285.5 | 286.3 | SUP-C31 | [] | ["C31"] | ZD1 / DZ-2 | ["2CCE0","2CD63","2CCF8","2CD9C","2CCED","2CCEE","2CD87","2CEC1","2CE9C"] | SUP-C31/Cimentación de soporte de tuberías C31 · pedestal de hormigón | foundation | Geometría de fabricante; implantación absoluta provisional |  | Cimentaciones de equipos y pedestales del fabricante · revisión recibida 04/09/2026 | 2CCE0, 2CD63, 2CCF8, 2CD9C, 2CCED, 2CCEE, 2CD87, 2CEC1, 2CE9C | -0.6 | 0.2 | 0.25 | Cotas relativas del dibujo. La equivalencia con un datum absoluto está pendiente. | Z del modelo = cota relativa + 1,10 m. Correspondencia provisional con 286,10 m; no es cota de obra confirmada. | Contornos y sección documentados por el fabricante | 0.5 | 0.5 | Material: Hormigón HA-30
Cimentación de soporte de tuberías C32 · cuerpo de hormigón | Parcela industrial Jinhong | Cimentación industrial | Cimentaciones de equipos y pedestales del fabricante · revisión recibida 04/09/2026 | 1.12689 | 1.12689 | 0.4 | 3.6 | 0.4 | process_plant | Zona de separación de aire | {"name":"Hormigón HA-30","status":"documentado","source":"Nota general de pedestales 2CED5"} | {"documented":[{"label":"Extensión local X","value":1.0,"unit":"m","source":"2CCE1, 2CD64, 2CCF9, 2CD9D, 2CCEA, 2CCEB, 2CD88, 2CEC2, 2CE9D","status":"derivada del contorno CAD"},{"label":"Extensión local Y","value":1.0,"unit":"m","source":"2CCE1, 2CD64, 2CCF9, 2CD9D, 2CCEA, 2CCEB, 2CD88, 2CEC2, 2CE9D","status":"derivada del contorno CAD"},{"label":"Cota inferior relativa adoptada","value":-1.0,"unit":"m","source":"ZD1 / DZ-2","status":"documentada"},{"label":"Cota superior relativa adoptada","value":-0.6,"unit":"m","source":"ZD1 / DZ-2","status":"documentada / separación por material"}],"geometry":[{"label":"Extensión de la malla en X","value":1.1268850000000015,"unit":"m","source":"Geometría releída del IFC; datum absoluto de proceso provisional","status":"derivado"},{"label":"Extensión de la malla en Y","value":1.1268850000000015,"unit":"m","source":"Geometría releída del IFC; datum absoluto de proceso provisional","status":"derivado"},{"label":"Extensión de la malla en Z","value":0.4,"unit":"m","source":"Geometría releída del IFC; datum absoluto de proceso provisional","status":"derivado"},{"label":"Cota inferior de visualización","value":285.1,"unit":"m","source":"Geometría releída del IFC; datum absoluto de proceso provisional","status":"derivado"},{"label":"Cota superior de visualización","value":285.5,"unit":"m","source":"Geometría releída del IFC; datum absoluto de proceso provisional","status":"derivado"}]} | {"documentId":"LHD2609-JG00100-20260904","title":"Cimentaciones de equipos y pedestales del fabricante · revisión recibida 04/09/2026","date":"2026-09-04","sheet":"ZD1 / DZ-2","fileName":"LHD2609-JG00100_20260904.dwg","revisionCaveat":"Fecha de revisión tomada del nombre recibido; cajetines internos mantienen 02/07/2026 y algunos textos de plantilla.","sourceFileSha256":"b42eb027b7bc0b14c38d1d13514f4899b58a732aa8d0ba2ccf10fa2fc3192890"} | provisional | [] | {"Cota inferior relativa (m)":-1.0,"Cota superior relativa (m)":-0.6,"Cero absoluto de visualización (m)":286.1,"Estado del cero absoluto":"Provisional","Criterio":"Las cotas relativas proceden del dibujo; la equivalencia absoluta no está confirmada."} | {"boundingBoxM":{"min":[46.395664,44.677859,0.1],"max":[47.522549,45.804744,0.5]},"extentsM":[1.126885,1.126885,0.4],"meshSurfaceM2":3.600001,"meshVolumeM3":0.4,"closedSolid":true,"basis":"Magnitudes de las mallas representadas, no cantidades certificadas de obra, compra o fabricación. Las partes pueden compartir superficies; no se suman como un despiece de materiales."} | {"profileId":"concrete_ha30","name":"Hormigón HA-30","materialName":"Hormigón HA-30","physicalMaterialStatus":"documentado","physicalMaterialSource":"Nota general de pedestales 2CED5","appearanceStatus":"criterio_visual","appearanceBasis":"Interpretación visual del material documental; el acabado, tono y parámetros PBR no son una especificación contractual.","note":"La apariencia gráfica no modifica ni confirma la especificación física del material."} | {"elementId":"found_0904_a9ee1466a89f59","ifcGuid":"27fvd4MQ9VyfYYo43OobzV","ifcClass":"IfcFooting","buildingId":"process_plant","buildingName":"Zona de separación de aire","sourceDocumentId":"LHD2609-JG00100-20260904","sourceRepresentationKind":"foundation"} | {"layerId":"foundations","layerName":"Cimentaciones","role":"Cimentación industrial","basis":"Clasificación por función del elemento; no modifica las especificaciones documentales."} | {"profileId":"concrete_ha30","name":"Hormigón HA-30","status":"criterio_visual","basis":"Interpretación visual del material documental; el acabado, tono y parámetros PBR no son una especificación contractual.","physicalMaterialUnchanged":true} | 0.4 | Hormigón HA-30 | Hormigón HA-30 | found_0904_a9ee1466a89f59 | Nota general de pedestales 2CED5 | documentado | concrete_ha30 | [0.658824,0.658824,0.623529] | 0.94 | Zona de separación de aire; BIM · Cimentaciones | 1.12689 | 1.12689 | 0.4 | 285.1 | 285.5 | SUP-C32 | [] | ["C32"] | ZD1 / DZ-2 | ["2CCE1","2CD64","2CCF9","2CD9D","2CCEA","2CCEB","2CD88","2CEC2","2CE9D"] | SUP-C32/Cimentación de soporte de tuberías C32 · cuerpo de hormigón | foundation | Geometría de fabricante; implantación absoluta provisional |  | Cimentaciones de equipos y pedestales del fabricante · revisión recibida 04/09/2026 | 2CCE1, 2CD64, 2CCF9, 2CD9D, 2CCEA, 2CCEB, 2CD88, 2CEC2, 2CE9D | -1 | -0.6 | 1 | Cotas relativas del dibujo. La equivalencia con un datum absoluto está pendiente. | Z del modelo = cota relativa + 1,10 m. Correspondencia provisional con 286,10 m; no es cota de obra confirmada. | Contornos y sección documentados por el fabricante | 1 | 1 | Material: Hormigón HA-30
Cimentación de soporte de tuberías C32 · pedestal de hormigón | Parcela industrial Jinhong | Cimentación industrial | Cimentaciones de equipos y pedestales del fabricante · revisión recibida 04/09/2026 | 0.563443 | 0.563443 | 0.8 | 2.1 | 0.2 | process_plant | Zona de separación de aire | {"name":"Hormigón HA-30","status":"documentado","source":"Nota general de pedestales 2CED5"} | {"documented":[{"label":"Extensión local X","value":0.5,"unit":"m","source":"2CCE1, 2CD64, 2CCF9, 2CD9D, 2CCEA, 2CCEB, 2CD88, 2CEC2, 2CE9D","status":"derivada del contorno CAD"},{"label":"Extensión local Y","value":0.5,"unit":"m","source":"2CCE1, 2CD64, 2CCF9, 2CD9D, 2CCEA, 2CCEB, 2CD88, 2CEC2, 2CE9D","status":"derivada del contorno CAD"},{"label":"Cota inferior relativa adoptada","value":-0.6,"unit":"m","source":"ZD1 / DZ-2","status":"documentada"},{"label":"Cota superior relativa adoptada","value":0.2,"unit":"m","source":"ZD1 / DZ-2","status":"documentada / separación por material"}],"geometry":[{"label":"Extensión de la malla en X","value":0.5634429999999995,"unit":"m","source":"Geometría releída del IFC; datum absoluto de proceso provisional","status":"derivado"},{"label":"Extensión de la malla en Y","value":0.5634429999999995,"unit":"m","source":"Geometría releída del IFC; datum absoluto de proceso provisional","status":"derivado"},{"label":"Extensión de la malla en Z","value":0.8,"unit":"m","source":"Geometría releída del IFC; datum absoluto de proceso provisional","status":"derivado"},{"label":"Cota inferior de visualización","value":285.5,"unit":"m","source":"Geometría releída del IFC; datum absoluto de proceso provisional","status":"derivado"},{"label":"Cota superior de visualización","value":286.3,"unit":"m","source":"Geometría releída del IFC; datum absoluto de proceso provisional","status":"derivado"}]} | {"documentId":"LHD2609-JG00100-20260904","title":"Cimentaciones de equipos y pedestales del fabricante · revisión recibida 04/09/2026","date":"2026-09-04","sheet":"ZD1 / DZ-2","fileName":"LHD2609-JG00100_20260904.dwg","revisionCaveat":"Fecha de revisión tomada del nombre recibido; cajetines internos mantienen 02/07/2026 y algunos textos de plantilla.","sourceFileSha256":"b42eb027b7bc0b14c38d1d13514f4899b58a732aa8d0ba2ccf10fa2fc3192890"} | provisional | [] | {"Cota inferior relativa (m)":-0.6,"Cota superior relativa (m)":0.2,"Cero absoluto de visualización (m)":286.1,"Estado del cero absoluto":"Provisional","Criterio":"Las cotas relativas proceden del dibujo; la equivalencia absoluta no está confirmada."} | {"boundingBoxM":{"min":[46.677385,44.95958,0.5],"max":[47.240828,45.523023,1.3]},"extentsM":[0.563443,0.563443,0.8],"meshSurfaceM2":2.100003,"meshVolumeM3":0.2,"closedSolid":true,"basis":"Magnitudes de las mallas representadas, no cantidades certificadas de obra, compra o fabricación. Las partes pueden compartir superficies; no se suman como un despiece de materiales."} | {"profileId":"concrete_ha30","name":"Hormigón HA-30","materialName":"Hormigón HA-30","physicalMaterialStatus":"documentado","physicalMaterialSource":"Nota general de pedestales 2CED5","appearanceStatus":"criterio_visual","appearanceBasis":"Interpretación visual del material documental; el acabado, tono y parámetros PBR no son una especificación contractual.","note":"La apariencia gráfica no modifica ni confirma la especificación física del material."} | {"elementId":"found_0904_d39f27785d3983","ifcGuid":"0SSXcrA_PPhOZjfB9SE402","ifcClass":"IfcFooting","buildingId":"process_plant","buildingName":"Zona de separación de aire","sourceDocumentId":"LHD2609-JG00100-20260904","sourceRepresentationKind":"foundation"} | {"layerId":"foundations","layerName":"Cimentaciones","role":"Cimentación industrial","basis":"Clasificación por función del elemento; no modifica las especificaciones documentales."} | {"profileId":"concrete_ha30","name":"Hormigón HA-30","status":"criterio_visual","basis":"Interpretación visual del material documental; el acabado, tono y parámetros PBR no son una especificación contractual.","physicalMaterialUnchanged":true} | 0.2 | Hormigón HA-30 | Hormigón HA-30 | found_0904_d39f27785d3983 | Nota general de pedestales 2CED5 | documentado | concrete_ha30 | [0.658824,0.658824,0.623529] | 0.94 | Zona de separación de aire; BIM · Cimentaciones | 0.563443 | 0.563443 | 0.8 | 285.5 | 286.3 | SUP-C32 | [] | ["C32"] | ZD1 / DZ-2 | ["2CCE1","2CD64","2CCF9","2CD9D","2CCEA","2CCEB","2CD88","2CEC2","2CE9D"] | SUP-C32/Cimentación de soporte de tuberías C32 · pedestal de hormigón | foundation | Geometría de fabricante; implantación absoluta provisional |  | Cimentaciones de equipos y pedestales del fabricante · revisión recibida 04/09/2026 | 2CCE1, 2CD64, 2CCF9, 2CD9D, 2CCEA, 2CCEB, 2CD88, 2CEC2, 2CE9D | -0.6 | 0.2 | 0.25 | Cotas relativas del dibujo. La equivalencia con un datum absoluto está pendiente. | Z del modelo = cota relativa + 1,10 m. Correspondencia provisional con 286,10 m; no es cota de obra confirmada. | Contornos y sección documentados por el fabricante | 0.5 | 0.5 | Material: Hormigón HA-30
Cimentación de soporte de tuberías C33 · cuerpo de hormigón | Parcela industrial Jinhong | Cimentación industrial | Cimentaciones de equipos y pedestales del fabricante · revisión recibida 04/09/2026 | 1.12689 | 1.12688 | 0.4 | 3.6 | 0.4 | process_plant | Zona de separación de aire | {"name":"Hormigón HA-30","status":"documentado","source":"Nota general de pedestales 2CED5"} | {"documented":[{"label":"Extensión local X","value":1.0,"unit":"m","source":"2CD0A, 2CD58, 2CD22, 2CD9E, 2CD13, 2CD14, 2CD89, 2CEC3, 2CE9E","status":"derivada del contorno CAD"},{"label":"Extensión local Y","value":1.0,"unit":"m","source":"2CD0A, 2CD58, 2CD22, 2CD9E, 2CD13, 2CD14, 2CD89, 2CEC3, 2CE9E","status":"derivada del contorno CAD"},{"label":"Cota inferior relativa adoptada","value":-1.0,"unit":"m","source":"ZD1 / DZ-2","status":"documentada"},{"label":"Cota superior relativa adoptada","value":-0.6,"unit":"m","source":"ZD1 / DZ-2","status":"documentada / separación por material"}],"geometry":[{"label":"Extensión de la malla en X","value":1.1268850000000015,"unit":"m","source":"Geometría releída del IFC; datum absoluto de proceso provisional","status":"derivado"},{"label":"Extensión de la malla en Y","value":1.1268849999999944,"unit":"m","source":"Geometría releída del IFC; datum absoluto de proceso provisional","status":"derivado"},{"label":"Extensión de la malla en Z","value":0.4,"unit":"m","source":"Geometría releída del IFC; datum absoluto de proceso provisional","status":"derivado"},{"label":"Cota inferior de visualización","value":285.1,"unit":"m","source":"Geometría releída del IFC; datum absoluto de proceso provisional","status":"derivado"},{"label":"Cota superior de visualización","value":285.5,"unit":"m","source":"Geometría releída del IFC; datum absoluto de proceso provisional","status":"derivado"}]} | {"documentId":"LHD2609-JG00100-20260904","title":"Cimentaciones de equipos y pedestales del fabricante · revisión recibida 04/09/2026","date":"2026-09-04","sheet":"ZD1 / DZ-2","fileName":"LHD2609-JG00100_20260904.dwg","revisionCaveat":"Fecha de revisión tomada del nombre recibido; cajetines internos mantienen 02/07/2026 y algunos textos de plantilla.","sourceFileSha256":"b42eb027b7bc0b14c38d1d13514f4899b58a732aa8d0ba2ccf10fa2fc3192890"} | provisional | [] | {"Cota inferior relativa (m)":-1.0,"Cota superior relativa (m)":-0.6,"Cero absoluto de visualización (m)":286.1,"Estado del cero absoluto":"Provisional","Criterio":"Las cotas relativas proceden del dibujo; la equivalencia absoluta no está confirmada."} | {"boundingBoxM":{"min":[50.703204,48.476556,0.1],"max":[51.830089,49.603441,0.5]},"extentsM":[1.126885,1.126885,0.4],"meshSurfaceM2":3.600001,"meshVolumeM3":0.4,"closedSolid":true,"basis":"Magnitudes de las mallas representadas, no cantidades certificadas de obra, compra o fabricación. Las partes pueden compartir superficies; no se suman como un despiece de materiales."} | {"profileId":"concrete_ha30","name":"Hormigón HA-30","materialName":"Hormigón HA-30","physicalMaterialStatus":"documentado","physicalMaterialSource":"Nota general de pedestales 2CED5","appearanceStatus":"criterio_visual","appearanceBasis":"Interpretación visual del material documental; el acabado, tono y parámetros PBR no son una especificación contractual.","note":"La apariencia gráfica no modifica ni confirma la especificación física del material."} | {"elementId":"found_0904_3f0498b6535ab1","ifcGuid":"1Va6o$E69TXO9VSNoEIfRt","ifcClass":"IfcFooting","buildingId":"process_plant","buildingName":"Zona de separación de aire","sourceDocumentId":"LHD2609-JG00100-20260904","sourceRepresentationKind":"foundation"} | {"layerId":"foundations","layerName":"Cimentaciones","role":"Cimentación industrial","basis":"Clasificación por función del elemento; no modifica las especificaciones documentales."} | {"profileId":"concrete_ha30","name":"Hormigón HA-30","status":"criterio_visual","basis":"Interpretación visual del material documental; el acabado, tono y parámetros PBR no son una especificación contractual.","physicalMaterialUnchanged":true} | 0.4 | Hormigón HA-30 | Hormigón HA-30 | found_0904_3f0498b6535ab1 | Nota general de pedestales 2CED5 | documentado | concrete_ha30 | [0.658824,0.658824,0.623529] | 0.94 | Zona de separación de aire; BIM · Cimentaciones | 1.12689 | 1.12688 | 0.4 | 285.1 | 285.5 | SUP-C33 | [] | ["C33"] | ZD1 / DZ-2 | ["2CD0A","2CD58","2CD22","2CD9E","2CD13","2CD14","2CD89","2CEC3","2CE9E"] | SUP-C33/Cimentación de soporte de tuberías C33 · cuerpo de hormigón | foundation | Geometría de fabricante; implantación absoluta provisional |  | Cimentaciones de equipos y pedestales del fabricante · revisión recibida 04/09/2026 | 2CD0A, 2CD58, 2CD22, 2CD9E, 2CD13, 2CD14, 2CD89, 2CEC3, 2CE9E | -1 | -0.6 | 1 | Cotas relativas del dibujo. La equivalencia con un datum absoluto está pendiente. | Z del modelo = cota relativa + 1,10 m. Correspondencia provisional con 286,10 m; no es cota de obra confirmada. | Contornos y sección documentados por el fabricante | 1 | 1 | Material: Hormigón HA-30
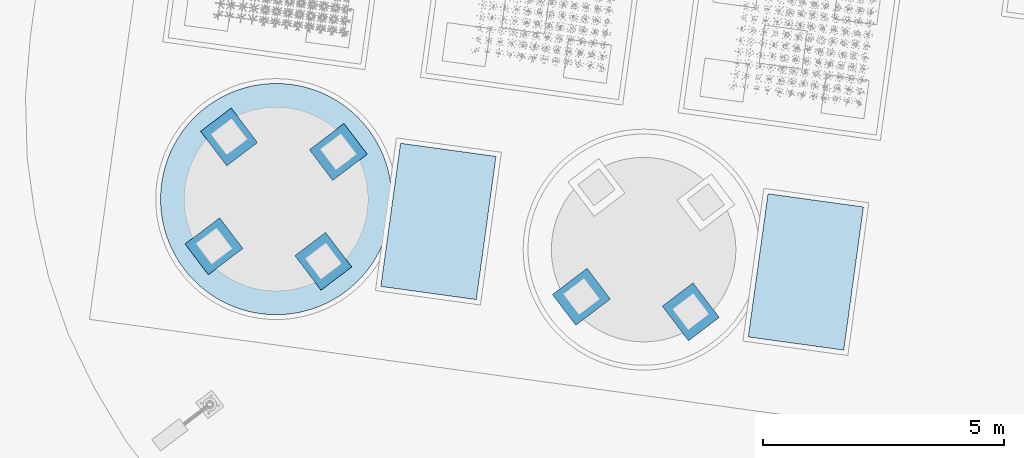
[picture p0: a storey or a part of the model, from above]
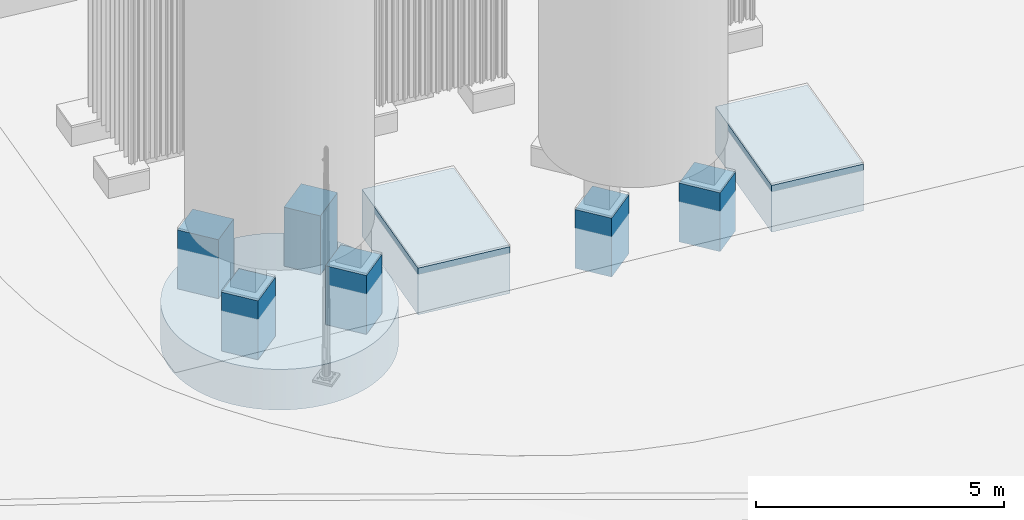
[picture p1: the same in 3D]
Properties of the parts of a building model (IFC4), part 84 of 134

# IfcFooting (214)
Name | In | Description = category = Categoria = Funcion | Document | ExtensionX (m) | ExtensionY (m) | ExtensionZ (m) | SuperficieDeLaMalla (m2) | VolumenGeometrico (m3) | buildingId | buildingName | material | dimensions | JH_InformacionBIM, source = DocumentoFuente | JH_InformacionBIM, status = EstadoDeInformacion | issues = IncidenciasPendientes | positioning = PosicionYEstado | geometryMetrics | materialAppearance | visualizationIdentity | classification | appearance | Volumen geométrico (m³) | JH_Trazabilidad, Material = name | Acabado de visualización = Acabado | Identificador | JH_EvidenciaDeMaterial, source | JH_EvidenciaDeMaterial, status | Perfil | ColorRGB | Rugosidad | Group | Extensión de la malla en X (m) | Extensión de la malla en Y (m) | Extensión de la malla en Z (m) = Espesor o altura real de sección (m) | Cota inferior de visualización (m) | Cota superior de visualización (m) | assemblyId = Conjunto de cimentación | equipmentIds | supportPositionIds | sectionRef = Sección de referencia | sourceCadHandles | stableElementKey | representationKind | geometryStatus | Equipos asociados | Documento de origen | Identificadores CAD de referencia | Cota inferior relativa (m) = Cota inferior relativa adoptada (m) | Cota superior relativa (m) = Cota superior relativa adoptada (m) | Área de planta (m²) | Referencia vertical | Implantación para visualización | Estado de la geometría | Extensión local X (m) | Extensión local Y (m) | Incidencias de origen
Cimentación de soporte de tuberías C33 · pedestal de hormigón | Parcela industrial Jinhong | Cimentación industrial | Cimentaciones de equipos y pedestales del fabricante · revisión recibida 04/09/2026 | 0.563443 | 0.563443 | 0.7 | 1.9 | 0.175 | process_plant | Zona de separación de aire | {"name":"Hormigón HA-30","status":"documentado","source":"Nota general de pedestales 2CED5"} | {"documented":[{"label":"Extensión local X","value":0.5,"unit":"m","source":"2CD0A, 2CD58, 2CD22, 2CD9E, 2CD13, 2CD14, 2CD89, 2CEC3, 2CE9E","status":"derivada del contorno CAD"},{"label":"Extensión local Y","value":0.5,"unit":"m","source":"2CD0A, 2CD58, 2CD22, 2CD9E, 2CD13, 2CD14, 2CD89, 2CEC3, 2CE9E","status":"derivada del contorno CAD"},{"label":"Cota inferior relativa adoptada","value":-0.6,"unit":"m","source":"ZD1 / DZ-2","status":"documentada"},{"label":"Cota superior relativa adoptada","value":0.1,"unit":"m","source":"ZD1 / DZ-2","status":"documentada / separación por material"}],"geometry":[{"label":"Extensión de la malla en X","value":0.5634430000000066,"unit":"m","source":"Geometría releída del IFC; datum absoluto de proceso provisional","status":"derivado"},{"label":"Extensión de la malla en Y","value":0.5634429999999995,"unit":"m","source":"Geometría releída del IFC; datum absoluto de proceso provisional","status":"derivado"},{"label":"Extensión de la malla en Z","value":0.7,"unit":"m","source":"Geometría releída del IFC; datum absoluto de proceso provisional","status":"derivado"},{"label":"Cota inferior de visualización","value":285.5,"unit":"m","source":"Geometría releída del IFC; datum absoluto de proceso provisional","status":"derivado"},{"label":"Cota superior de visualización","value":286.2,"unit":"m","source":"Geometría releída del IFC; datum absoluto de proceso provisional","status":"derivado"}]} | {"documentId":"LHD2609-JG00100-20260904","title":"Cimentaciones de equipos y pedestales del fabricante · revisión recibida 04/09/2026","date":"2026-09-04","sheet":"ZD1 / DZ-2","fileName":"LHD2609-JG00100_20260904.dwg","revisionCaveat":"Fecha de revisión tomada del nombre recibido; cajetines internos mantienen 02/07/2026 y algunos textos de plantilla.","sourceFileSha256":"b42eb027b7bc0b14c38d1d13514f4899b58a732aa8d0ba2ccf10fa2fc3192890"} | provisional | [] | {"Cota inferior relativa (m)":-0.6,"Cota superior relativa (m)":0.1,"Cero absoluto de visualización (m)":286.1,"Estado del cero absoluto":"Provisional","Criterio":"Las cotas relativas proceden del dibujo; la equivalencia absoluta no está confirmada."} | {"boundingBoxM":{"min":[50.984925,48.758277,0.5],"max":[51.548368,49.32172,1.2]},"extentsM":[0.563443,0.563443,0.7],"meshSurfaceM2":1.900003,"meshVolumeM3":0.175,"closedSolid":true,"basis":"Magnitudes de las mallas representadas, no cantidades certificadas de obra, compra o fabricación. Las partes pueden compartir superficies; no se suman como un despiece de materiales."} | {"profileId":"concrete_ha30","name":"Hormigón HA-30","materialName":"Hormigón HA-30","physicalMaterialStatus":"documentado","physicalMaterialSource":"Nota general de pedestales 2CED5","appearanceStatus":"criterio_visual","appearanceBasis":"Interpretación visual del material documental; el acabado, tono y parámetros PBR no son una especificación contractual.","note":"La apariencia gráfica no modifica ni confirma la especificación física del material."} | {"elementId":"found_0904_09a874146d8e2c","ifcGuid":"0KxBDxYCjOpwqsddu7jCLK","ifcClass":"IfcFooting","buildingId":"process_plant","buildingName":"Zona de separación de aire","sourceDocumentId":"LHD2609-JG00100-20260904","sourceRepresentationKind":"foundation"} | {"layerId":"foundations","layerName":"Cimentaciones","role":"Cimentación industrial","basis":"Clasificación por función del elemento; no modifica las especificaciones documentales."} | {"profileId":"concrete_ha30","name":"Hormigón HA-30","status":"criterio_visual","basis":"Interpretación visual del material documental; el acabado, tono y parámetros PBR no son una especificación contractual.","physicalMaterialUnchanged":true} | 0.175 | Hormigón HA-30 | Hormigón HA-30 | found_0904_09a874146d8e2c | Nota general de pedestales 2CED5 | documentado | concrete_ha30 | [0.658824,0.658824,0.623529] | 0.94 | Zona de separación de aire; BIM · Cimentaciones | 0.563443 | 0.563443 | 0.7 | 285.5 | 286.2 | SUP-C33 | [] | ["C33"] | ZD1 / DZ-2 | ["2CD0A","2CD58","2CD22","2CD9E","2CD13","2CD14","2CD89","2CEC3","2CE9E"] | SUP-C33/Cimentación de soporte de tuberías C33 · pedestal de hormigón | foundation | Geometría de fabricante; implantación absoluta provisional |  | Cimentaciones de equipos y pedestales del fabricante · revisión recibida 04/09/2026 | 2CD0A, 2CD58, 2CD22, 2CD9E, 2CD13, 2CD14, 2CD89, 2CEC3, 2CE9E | -0.6 | 0.1 | 0.25 | Cotas relativas del dibujo. La equivalencia con un datum absoluto está pendiente. | Z del modelo = cota relativa + 1,10 m. Correspondencia provisional con 286,10 m; no es cota de obra confirmada. | Contornos y sección documentados por el fabricante | 0.5 | 0.5 | Material: Hormigón HA-30
Cimentación de soporte de tuberías C34 · cuerpo de hormigón | Parcela industrial Jinhong | Cimentación industrial | Cimentaciones de equipos y pedestales del fabricante · revisión recibida 04/09/2026 | 1.12689 | 1.12689 | 0.4 | 3.6 | 0.4 | process_plant | Zona de separación de aire | {"name":"Hormigón HA-30","status":"documentado","source":"Nota general de pedestales 2CED5"} | {"documented":[{"label":"Extensión local X","value":1.0,"unit":"m","source":"2CD0B, 2CD66, 2CD23, 2CD9F, 2CD12, 2CD15, 2CD8A, 2CEC4, 2CE9F","status":"derivada del contorno CAD"},{"label":"Extensión local Y","value":1.0,"unit":"m","source":"2CD0B, 2CD66, 2CD23, 2CD9F, 2CD12, 2CD15, 2CD8A, 2CEC4, 2CE9F","status":"derivada del contorno CAD"},{"label":"Cota inferior relativa adoptada","value":-1.0,"unit":"m","source":"ZD1 / DZ-2","status":"documentada"},{"label":"Cota superior relativa adoptada","value":-0.6,"unit":"m","source":"ZD1 / DZ-2","status":"documentada / separación por material"}],"geometry":[{"label":"Extensión de la malla en X","value":1.1268850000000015,"unit":"m","source":"Geometría releída del IFC; datum absoluto de proceso provisional","status":"derivado"},{"label":"Extensión de la malla en Y","value":1.1268850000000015,"unit":"m","source":"Geometría releída del IFC; datum absoluto de proceso provisional","status":"derivado"},{"label":"Extensión de la malla en Z","value":0.4,"unit":"m","source":"Geometría releída del IFC; datum absoluto de proceso provisional","status":"derivado"},{"label":"Cota inferior de visualización","value":285.1,"unit":"m","source":"Geometría releída del IFC; datum absoluto de proceso provisional","status":"derivado"},{"label":"Cota superior de visualización","value":285.5,"unit":"m","source":"Geometría releída del IFC; datum absoluto de proceso provisional","status":"derivado"}]} | {"documentId":"LHD2609-JG00100-20260904","title":"Cimentaciones de equipos y pedestales del fabricante · revisión recibida 04/09/2026","date":"2026-09-04","sheet":"ZD1 / DZ-2","fileName":"LHD2609-JG00100_20260904.dwg","revisionCaveat":"Fecha de revisión tomada del nombre recibido; cajetines internos mantienen 02/07/2026 y algunos textos de plantilla.","sourceFileSha256":"b42eb027b7bc0b14c38d1d13514f4899b58a732aa8d0ba2ccf10fa2fc3192890"} | provisional | [] | {"Cota inferior relativa (m)":-1.0,"Cota superior relativa (m)":-0.6,"Cero absoluto de visualización (m)":286.1,"Estado del cero absoluto":"Provisional","Criterio":"Las cotas relativas proceden del dibujo; la equivalencia absoluta no está confirmada."} | {"boundingBoxM":{"min":[59.598319,44.528211,0.1],"max":[60.725204,45.655096,0.5]},"extentsM":[1.126885,1.126885,0.4],"meshSurfaceM2":3.600001,"meshVolumeM3":0.4,"closedSolid":true,"basis":"Magnitudes de las mallas representadas, no cantidades certificadas de obra, compra o fabricación. Las partes pueden compartir superficies; no se suman como un despiece de materiales."} | {"profileId":"concrete_ha30","name":"Hormigón HA-30","materialName":"Hormigón HA-30","physicalMaterialStatus":"documentado","physicalMaterialSource":"Nota general de pedestales 2CED5","appearanceStatus":"criterio_visual","appearanceBasis":"Interpretación visual del material documental; el acabado, tono y parámetros PBR no son una especificación contractual.","note":"La apariencia gráfica no modifica ni confirma la especificación física del material."} | {"elementId":"found_0904_ac3fc66a89f606","ifcGuid":"1mVcpM1XTMfA1tgb_P7VfO","ifcClass":"IfcFooting","buildingId":"process_plant","buildingName":"Zona de separación de aire","sourceDocumentId":"LHD2609-JG00100-20260904","sourceRepresentationKind":"foundation"} | {"layerId":"foundations","layerName":"Cimentaciones","role":"Cimentación industrial","basis":"Clasificación por función del elemento; no modifica las especificaciones documentales."} | {"profileId":"concrete_ha30","name":"Hormigón HA-30","status":"criterio_visual","basis":"Interpretación visual del material documental; el acabado, tono y parámetros PBR no son una especificación contractual.","physicalMaterialUnchanged":true} | 0.4 | Hormigón HA-30 | Hormigón HA-30 | found_0904_ac3fc66a89f606 | Nota general de pedestales 2CED5 | documentado | concrete_ha30 | [0.658824,0.658824,0.623529] | 0.94 | Zona de separación de aire; BIM · Cimentaciones | 1.12689 | 1.12689 | 0.4 | 285.1 | 285.5 | SUP-C34 | [] | ["C34"] | ZD1 / DZ-2 | ["2CD0B","2CD66","2CD23","2CD9F","2CD12","2CD15","2CD8A","2CEC4","2CE9F"] | SUP-C34/Cimentación de soporte de tuberías C34 · cuerpo de hormigón | foundation | Geometría de fabricante; implantación absoluta provisional |  | Cimentaciones de equipos y pedestales del fabricante · revisión recibida 04/09/2026 | 2CD0B, 2CD66, 2CD23, 2CD9F, 2CD12, 2CD15, 2CD8A, 2CEC4, 2CE9F | -1 | -0.6 | 1 | Cotas relativas del dibujo. La equivalencia con un datum absoluto está pendiente. | Z del modelo = cota relativa + 1,10 m. Correspondencia provisional con 286,10 m; no es cota de obra confirmada. | Contornos y sección documentados por el fabricante | 1 | 1 | Material: Hormigón HA-30
Cimentación de soporte de tuberías C34 · pedestal de hormigón | Parcela industrial Jinhong | Cimentación industrial | Cimentaciones de equipos y pedestales del fabricante · revisión recibida 04/09/2026 | 0.563443 | 0.563443 | 0.8 | 2.1 | 0.2 | process_plant | Zona de separación de aire | {"name":"Hormigón HA-30","status":"documentado","source":"Nota general de pedestales 2CED5"} | {"documented":[{"label":"Extensión local X","value":0.5,"unit":"m","source":"2CD0B, 2CD66, 2CD23, 2CD9F, 2CD12, 2CD15, 2CD8A, 2CEC4, 2CE9F","status":"derivada del contorno CAD"},{"label":"Extensión local Y","value":0.5,"unit":"m","source":"2CD0B, 2CD66, 2CD23, 2CD9F, 2CD12, 2CD15, 2CD8A, 2CEC4, 2CE9F","status":"derivada del contorno CAD"},{"label":"Cota inferior relativa adoptada","value":-0.6,"unit":"m","source":"ZD1 / DZ-2","status":"documentada"},{"label":"Cota superior relativa adoptada","value":0.2,"unit":"m","source":"ZD1 / DZ-2","status":"documentada / separación por material"}],"geometry":[{"label":"Extensión de la malla en X","value":0.5634429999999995,"unit":"m","source":"Geometría releída del IFC; datum absoluto de proceso provisional","status":"derivado"},{"label":"Extensión de la malla en Y","value":0.5634429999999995,"unit":"m","source":"Geometría releída del IFC; datum absoluto de proceso provisional","status":"derivado"},{"label":"Extensión de la malla en Z","value":0.8,"unit":"m","source":"Geometría releída del IFC; datum absoluto de proceso provisional","status":"derivado"},{"label":"Cota inferior de visualización","value":285.5,"unit":"m","source":"Geometría releída del IFC; datum absoluto de proceso provisional","status":"derivado"},{"label":"Cota superior de visualización","value":286.3,"unit":"m","source":"Geometría releída del IFC; datum absoluto de proceso provisional","status":"derivado"}]} | {"documentId":"LHD2609-JG00100-20260904","title":"Cimentaciones de equipos y pedestales del fabricante · revisión recibida 04/09/2026","date":"2026-09-04","sheet":"ZD1 / DZ-2","fileName":"LHD2609-JG00100_20260904.dwg","revisionCaveat":"Fecha de revisión tomada del nombre recibido; cajetines internos mantienen 02/07/2026 y algunos textos de plantilla.","sourceFileSha256":"b42eb027b7bc0b14c38d1d13514f4899b58a732aa8d0ba2ccf10fa2fc3192890"} | provisional | [] | {"Cota inferior relativa (m)":-0.6,"Cota superior relativa (m)":0.2,"Cero absoluto de visualización (m)":286.1,"Estado del cero absoluto":"Provisional","Criterio":"Las cotas relativas proceden del dibujo; la equivalencia absoluta no está confirmada."} | {"boundingBoxM":{"min":[59.88004,44.809932,0.5],"max":[60.443483,45.373375,1.3]},"extentsM":[0.563443,0.563443,0.8],"meshSurfaceM2":2.100003,"meshVolumeM3":0.2,"closedSolid":true,"basis":"Magnitudes de las mallas representadas, no cantidades certificadas de obra, compra o fabricación. Las partes pueden compartir superficies; no se suman como un despiece de materiales."} | {"profileId":"concrete_ha30","name":"Hormigón HA-30","materialName":"Hormigón HA-30","physicalMaterialStatus":"documentado","physicalMaterialSource":"Nota general de pedestales 2CED5","appearanceStatus":"criterio_visual","appearanceBasis":"Interpretación visual del material documental; el acabado, tono y parámetros PBR no son una especificación contractual.","note":"La apariencia gráfica no modifica ni confirma la especificación física del material."} | {"elementId":"found_0904_690f4a8713cf43","ifcGuid":"1K3$4L7ovTSROiM5nLBgB1","ifcClass":"IfcFooting","buildingId":"process_plant","buildingName":"Zona de separación de aire","sourceDocumentId":"LHD2609-JG00100-20260904","sourceRepresentationKind":"foundation"} | {"layerId":"foundations","layerName":"Cimentaciones","role":"Cimentación industrial","basis":"Clasificación por función del elemento; no modifica las especificaciones documentales."} | {"profileId":"concrete_ha30","name":"Hormigón HA-30","status":"criterio_visual","basis":"Interpretación visual del material documental; el acabado, tono y parámetros PBR no son una especificación contractual.","physicalMaterialUnchanged":true} | 0.2 | Hormigón HA-30 | Hormigón HA-30 | found_0904_690f4a8713cf43 | Nota general de pedestales 2CED5 | documentado | concrete_ha30 | [0.658824,0.658824,0.623529] | 0.94 | Zona de separación de aire; BIM · Cimentaciones | 0.563443 | 0.563443 | 0.8 | 285.5 | 286.3 | SUP-C34 | [] | ["C34"] | ZD1 / DZ-2 | ["2CD0B","2CD66","2CD23","2CD9F","2CD12","2CD15","2CD8A","2CEC4","2CE9F"] | SUP-C34/Cimentación de soporte de tuberías C34 · pedestal de hormigón | foundation | Geometría de fabricante; implantación absoluta provisional |  | Cimentaciones de equipos y pedestales del fabricante · revisión recibida 04/09/2026 | 2CD0B, 2CD66, 2CD23, 2CD9F, 2CD12, 2CD15, 2CD8A, 2CEC4, 2CE9F | -0.6 | 0.2 | 0.25 | Cotas relativas del dibujo. La equivalencia con un datum absoluto está pendiente. | Z del modelo = cota relativa + 1,10 m. Correspondencia provisional con 286,10 m; no es cota de obra confirmada. | Contornos y sección documentados por el fabricante | 0.5 | 0.5 | Material: Hormigón HA-30
Cimentación de soporte de tuberías C35 · cuerpo de hormigón | Parcela industrial Jinhong | Cimentación industrial | Cimentaciones de equipos y pedestales del fabricante · revisión recibida 04/09/2026 | 1.12689 | 1.12689 | 0.4 | 3.6 | 0.4 | process_plant | Zona de separación de aire | {"name":"Hormigón HA-30","status":"documentado","source":"Nota general de pedestales 2CED5"} | {"documented":[{"label":"Extensión local X","value":1.0,"unit":"m","source":"2CD0C, 2CD65, 2CD24, 2CDA0, 2CD16, 2CD18, 2CD8B, 2CEC5, 2CEA0","status":"derivada del contorno CAD"},{"label":"Extensión local Y","value":1.0,"unit":"m","source":"2CD0C, 2CD65, 2CD24, 2CDA0, 2CD16, 2CD18, 2CD8B, 2CEC5, 2CEA0","status":"derivada del contorno CAD"},{"label":"Cota inferior relativa adoptada","value":-1.0,"unit":"m","source":"ZD1 / DZ-2","status":"interpretación con conflicto conservado"},{"label":"Cota superior relativa adoptada","value":-0.6,"unit":"m","source":"ZD1 / DZ-2","status":"documentada / separación por material"}],"geometry":[{"label":"Extensión de la malla en X","value":1.1268850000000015,"unit":"m","source":"Geometría releída del IFC; datum absoluto de proceso provisional","status":"derivado"},{"label":"Extensión de la malla en Y","value":1.1268850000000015,"unit":"m","source":"Geometría releída del IFC; datum absoluto de proceso provisional","status":"derivado"},{"label":"Extensión de la malla en Z","value":0.4,"unit":"m","source":"Geometría releída del IFC; datum absoluto de proceso provisional","status":"derivado"},{"label":"Cota inferior de visualización","value":285.1,"unit":"m","source":"Geometría releída del IFC; datum absoluto de proceso provisional","status":"derivado"},{"label":"Cota superior de visualización","value":285.5,"unit":"m","source":"Geometría releída del IFC; datum absoluto de proceso provisional","status":"derivado"}]} | {"documentId":"LHD2609-JG00100-20260904","title":"Cimentaciones de equipos y pedestales del fabricante · revisión recibida 04/09/2026","date":"2026-09-04","sheet":"ZD1 / DZ-2","fileName":"LHD2609-JG00100_20260904.dwg","revisionCaveat":"Fecha de revisión tomada del nombre recibido; cajetines internos mantienen 02/07/2026 y algunos textos de plantilla.","sourceFileSha256":"b42eb027b7bc0b14c38d1d13514f4899b58a732aa8d0ba2ccf10fa2fc3192890"} | provisional | ["Identificador original HA-35 en columna de posición; C35 se infiere por secuencia. Se conserva el original y no se interpreta como material."] | {"Cota inferior relativa (m)":-1.0,"Cota superior relativa (m)":-0.6,"Cero absoluto de visualización (m)":286.1,"Estado del cero absoluto":"Provisional","Criterio":"Las cotas relativas proceden del dibujo; la equivalencia absoluta no está confirmada."} | {"boundingBoxM":{"min":[60.539466,44.398817,0.1],"max":[61.666351,45.525702,0.5]},"extentsM":[1.126885,1.126885,0.4],"meshSurfaceM2":3.600001,"meshVolumeM3":0.4,"closedSolid":true,"basis":"Magnitudes de las mallas representadas, no cantidades certificadas de obra, compra o fabricación. Las partes pueden compartir superficies; no se suman como un despiece de materiales."} | {"profileId":"concrete_ha30","name":"Hormigón HA-30","materialName":"Hormigón HA-30","physicalMaterialStatus":"documentado","physicalMaterialSource":"Nota general de pedestales 2CED5","appearanceStatus":"criterio_visual","appearanceBasis":"Interpretación visual del material documental; el acabado, tono y parámetros PBR no son una especificación contractual.","note":"La apariencia gráfica no modifica ni confirma la especificación física del material."} | {"elementId":"found_0904_c4e8fe0724b939","ifcGuid":"0F4wCJwyjJyuAgIeAOHsZP","ifcClass":"IfcFooting","buildingId":"process_plant","buildingName":"Zona de separación de aire","sourceDocumentId":"LHD2609-JG00100-20260904","sourceRepresentationKind":"foundation"} | {"layerId":"foundations","layerName":"Cimentaciones","role":"Cimentación industrial","basis":"Clasificación por función del elemento; no modifica las especificaciones documentales."} | {"profileId":"concrete_ha30","name":"Hormigón HA-30","status":"criterio_visual","basis":"Interpretación visual del material documental; el acabado, tono y parámetros PBR no son una especificación contractual.","physicalMaterialUnchanged":true} | 0.4 | Hormigón HA-30 | Hormigón HA-30 | found_0904_c4e8fe0724b939 | Nota general de pedestales 2CED5 | documentado | concrete_ha30 | [0.658824,0.658824,0.623529] | 0.94 | Zona de separación de aire; BIM · Cimentaciones | 1.12689 | 1.12689 | 0.4 | 285.1 | 285.5 | SUP-C35 | [] | ["C35"] | ZD1 / DZ-2 | ["2CD0C","2CD65","2CD24","2CDA0","2CD16","2CD18","2CD8B","2CEC5","2CEA0"] | SUP-C35/Cimentación de soporte de tuberías C35 · cuerpo de hormigón | foundation | Geometría de fabricante; implantación absoluta provisional |  | Cimentaciones de equipos y pedestales del fabricante · revisión recibida 04/09/2026 | 2CD0C, 2CD65, 2CD24, 2CDA0, 2CD16, 2CD18, 2CD8B, 2CEC5, 2CEA0 | -1 | -0.6 | 1 | Cotas relativas del dibujo. La equivalencia con un datum absoluto está pendiente. | Z del modelo = cota relativa + 1,10 m. Correspondencia provisional con 286,10 m; no es cota de obra confirmada. | Sección y contornos del fabricante; incidencias conservadas | 1 | 1 | Identificador original HA-35 en columna de posición; C35 se infiere por secuencia. Se conserva el original y no se interpreta como material. | Material: Hormigón HA-30
Cimentación de soporte de tuberías C35 · pedestal de hormigón | Parcela industrial Jinhong | Cimentación industrial | Cimentaciones de equipos y pedestales del fabricante · revisión recibida 04/09/2026 | 0.563443 | 0.563443 | 0.8 | 2.1 | 0.2 | process_plant | Zona de separación de aire | {"name":"Hormigón HA-30","status":"documentado","source":"Nota general de pedestales 2CED5"} | {"documented":[{"label":"Extensión local X","value":0.5,"unit":"m","source":"2CD0C, 2CD65, 2CD24, 2CDA0, 2CD16, 2CD18, 2CD8B, 2CEC5, 2CEA0","status":"derivada del contorno CAD"},{"label":"Extensión local Y","value":0.5,"unit":"m","source":"2CD0C, 2CD65, 2CD24, 2CDA0, 2CD16, 2CD18, 2CD8B, 2CEC5, 2CEA0","status":"derivada del contorno CAD"},{"label":"Cota inferior relativa adoptada","value":-0.6,"unit":"m","source":"ZD1 / DZ-2","status":"interpretación con conflicto conservado"},{"label":"Cota superior relativa adoptada","value":0.2,"unit":"m","source":"ZD1 / DZ-2","status":"documentada / separación por material"}],"geometry":[{"label":"Extensión de la malla en X","value":0.5634429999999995,"unit":"m","source":"Geometría releída del IFC; datum absoluto de proceso provisional","status":"derivado"},{"label":"Extensión de la malla en Y","value":0.5634429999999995,"unit":"m","source":"Geometría releída del IFC; datum absoluto de proceso provisional","status":"derivado"},{"label":"Extensión de la malla en Z","value":0.8,"unit":"m","source":"Geometría releída del IFC; datum absoluto de proceso provisional","status":"derivado"},{"label":"Cota inferior de visualización","value":285.5,"unit":"m","source":"Geometría releída del IFC; datum absoluto de proceso provisional","status":"derivado"},{"label":"Cota superior de visualización","value":286.3,"unit":"m","source":"Geometría releída del IFC; datum absoluto de proceso provisional","status":"derivado"}]} | {"documentId":"LHD2609-JG00100-20260904","title":"Cimentaciones de equipos y pedestales del fabricante · revisión recibida 04/09/2026","date":"2026-09-04","sheet":"ZD1 / DZ-2","fileName":"LHD2609-JG00100_20260904.dwg","revisionCaveat":"Fecha de revisión tomada del nombre recibido; cajetines internos mantienen 02/07/2026 y algunos textos de plantilla.","sourceFileSha256":"b42eb027b7bc0b14c38d1d13514f4899b58a732aa8d0ba2ccf10fa2fc3192890"} | provisional | ["Identificador original HA-35 en columna de posición; C35 se infiere por secuencia. Se conserva el original y no se interpreta como material."] | {"Cota inferior relativa (m)":-0.6,"Cota superior relativa (m)":0.2,"Cero absoluto de visualización (m)":286.1,"Estado del cero absoluto":"Provisional","Criterio":"Las cotas relativas proceden del dibujo; la equivalencia absoluta no está confirmada."} | {"boundingBoxM":{"min":[60.821187,44.680538,0.5],"max":[61.38463,45.243981,1.3]},"extentsM":[0.563443,0.563443,0.8],"meshSurfaceM2":2.100003,"meshVolumeM3":0.2,"closedSolid":true,"basis":"Magnitudes de las mallas representadas, no cantidades certificadas de obra, compra o fabricación. Las partes pueden compartir superficies; no se suman como un despiece de materiales."} | {"profileId":"concrete_ha30","name":"Hormigón HA-30","materialName":"Hormigón HA-30","physicalMaterialStatus":"documentado","physicalMaterialSource":"Nota general de pedestales 2CED5","appearanceStatus":"criterio_visual","appearanceBasis":"Interpretación visual del material documental; el acabado, tono y parámetros PBR no son una especificación contractual.","note":"La apariencia gráfica no modifica ni confirma la especificación física del material."} | {"elementId":"found_0904_fae976efe5638a","ifcGuid":"0FGeoCKlTNOv4de2RkBMuf","ifcClass":"IfcFooting","buildingId":"process_plant","buildingName":"Zona de separación de aire","sourceDocumentId":"LHD2609-JG00100-20260904","sourceRepresentationKind":"foundation"} | {"layerId":"foundations","layerName":"Cimentaciones","role":"Cimentación industrial","basis":"Clasificación por función del elemento; no modifica las especificaciones documentales."} | {"profileId":"concrete_ha30","name":"Hormigón HA-30","status":"criterio_visual","basis":"Interpretación visual del material documental; el acabado, tono y parámetros PBR no son una especificación contractual.","physicalMaterialUnchanged":true} | 0.2 | Hormigón HA-30 | Hormigón HA-30 | found_0904_fae976efe5638a | Nota general de pedestales 2CED5 | documentado | concrete_ha30 | [0.658824,0.658824,0.623529] | 0.94 | Zona de separación de aire; BIM · Cimentaciones | 0.563443 | 0.563443 | 0.8 | 285.5 | 286.3 | SUP-C35 | [] | ["C35"] | ZD1 / DZ-2 | ["2CD0C","2CD65","2CD24","2CDA0","2CD16","2CD18","2CD8B","2CEC5","2CEA0"] | SUP-C35/Cimentación de soporte de tuberías C35 · pedestal de hormigón | foundation | Geometría de fabricante; implantación absoluta provisional |  | Cimentaciones de equipos y pedestales del fabricante · revisión recibida 04/09/2026 | 2CD0C, 2CD65, 2CD24, 2CDA0, 2CD16, 2CD18, 2CD8B, 2CEC5, 2CEA0 | -0.6 | 0.2 | 0.25 | Cotas relativas del dibujo. La equivalencia con un datum absoluto está pendiente. | Z del modelo = cota relativa + 1,10 m. Correspondencia provisional con 286,10 m; no es cota de obra confirmada. | Sección y contornos del fabricante; incidencias conservadas | 0.5 | 0.5 | Identificador original HA-35 en columna de posición; C35 se infiere por secuencia. Se conserva el original y no se interpreta como material. | Material: Hormigón HA-30
Cimentación de soporte de tuberías C36 · cuerpo de hormigón | Parcela industrial Jinhong | Cimentación industrial | Cimentaciones de equipos y pedestales del fabricante · revisión recibida 04/09/2026 | 1.12688 | 1.12689 | 0.4 | 3.6 | 0.4 | process_plant | Zona de separación de aire | {"name":"Hormigón HA-30","status":"documentado","source":"Nota general de pedestales 2CED5"} | {"documented":[{"label":"Extensión local X","value":1.0,"unit":"m","source":"2CD0D, 2CD59, 2CD25, 2CDA1, 2CD17, 2CD19, 2CD7C, 2CEC6, 2CEA1","status":"derivada del contorno CAD"},{"label":"Extensión local Y","value":1.0,"unit":"m","source":"2CD0D, 2CD59, 2CD25, 2CDA1, 2CD17, 2CD19, 2CD7C, 2CEC6, 2CEA1","status":"derivada del contorno CAD"},{"label":"Cota inferior relativa adoptada","value":-1.0,"unit":"m","source":"ZD1 / DZ-1","status":"documentada"},{"label":"Cota superior relativa adoptada","value":-0.6,"unit":"m","source":"ZD1 / DZ-1","status":"documentada / separación por material"}],"geometry":[{"label":"Extensión de la malla en X","value":1.1268849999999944,"unit":"m","source":"Geometría releída del IFC; datum absoluto de proceso provisional","status":"derivado"},{"label":"Extensión de la malla en Y","value":1.1268850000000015,"unit":"m","source":"Geometría releída del IFC; datum absoluto de proceso provisional","status":"derivado"},{"label":"Extensión de la malla en Z","value":0.4,"unit":"m","source":"Geometría releída del IFC; datum absoluto de proceso provisional","status":"derivado"},{"label":"Cota inferior de visualización","value":285.1,"unit":"m","source":"Geometría releída del IFC; datum absoluto de proceso provisional","status":"derivado"},{"label":"Cota superior de visualización","value":285.5,"unit":"m","source":"Geometría releída del IFC; datum absoluto de proceso provisional","status":"derivado"}]} | {"documentId":"LHD2609-JG00100-20260904","title":"Cimentaciones de equipos y pedestales del fabricante · revisión recibida 04/09/2026","date":"2026-09-04","sheet":"ZD1 / DZ-1","fileName":"LHD2609-JG00100_20260904.dwg","revisionCaveat":"Fecha de revisión tomada del nombre recibido; cajetines internos mantienen 02/07/2026 y algunos textos de plantilla.","sourceFileSha256":"b42eb027b7bc0b14c38d1d13514f4899b58a732aa8d0ba2ccf10fa2fc3192890"} | provisional | [] | {"Cota inferior relativa (m)":-1.0,"Cota superior relativa (m)":-0.6,"Cero absoluto de visualización (m)":286.1,"Estado del cero absoluto":"Provisional","Criterio":"Las cotas relativas proceden del dibujo; la equivalencia absoluta no está confirmada."} | {"boundingBoxM":{"min":[59.060895,43.188929,0.1],"max":[60.18778,44.315814,0.5]},"extentsM":[1.126885,1.126885,0.4],"meshSurfaceM2":3.600001,"meshVolumeM3":0.4,"closedSolid":true,"basis":"Magnitudes de las mallas representadas, no cantidades certificadas de obra, compra o fabricación. Las partes pueden compartir superficies; no se suman como un despiece de materiales."} | {"profileId":"concrete_ha30","name":"Hormigón HA-30","materialName":"Hormigón HA-30","physicalMaterialStatus":"documentado","physicalMaterialSource":"Nota general de pedestales 2CED5","appearanceStatus":"criterio_visual","appearanceBasis":"Interpretación visual del material documental; el acabado, tono y parámetros PBR no son una especificación contractual.","note":"La apariencia gráfica no modifica ni confirma la especificación física del material."} | {"elementId":"found_0904_bbe6c9d6cf2d63","ifcGuid":"3Dvxh6WWLTXPajUewZq4EJ","ifcClass":"IfcFooting","buildingId":"process_plant","buildingName":"Zona de separación de aire","sourceDocumentId":"LHD2609-JG00100-20260904","sourceRepresentationKind":"foundation"} | {"layerId":"foundations","layerName":"Cimentaciones","role":"Cimentación industrial","basis":"Clasificación por función del elemento; no modifica las especificaciones documentales."} | {"profileId":"concrete_ha30","name":"Hormigón HA-30","status":"criterio_visual","basis":"Interpretación visual del material documental; el acabado, tono y parámetros PBR no son una especificación contractual.","physicalMaterialUnchanged":true} | 0.4 | Hormigón HA-30 | Hormigón HA-30 | found_0904_bbe6c9d6cf2d63 | Nota general de pedestales 2CED5 | documentado | concrete_ha30 | [0.658824,0.658824,0.623529] | 0.94 | Zona de separación de aire; BIM · Cimentaciones | 1.12688 | 1.12689 | 0.4 | 285.1 | 285.5 | SUP-C36 | [] | ["C36"] | ZD1 / DZ-1 | ["2CD0D","2CD59","2CD25","2CDA1","2CD17","2CD19","2CD7C","2CEC6","2CEA1"] | SUP-C36/Cimentación de soporte de tuberías C36 · cuerpo de hormigón | foundation | Geometría de fabricante; implantación absoluta provisional |  | Cimentaciones de equipos y pedestales del fabricante · revisión recibida 04/09/2026 | 2CD0D, 2CD59, 2CD25, 2CDA1, 2CD17, 2CD19, 2CD7C, 2CEC6, 2CEA1 | -1 | -0.6 | 1 | Cotas relativas del dibujo. La equivalencia con un datum absoluto está pendiente. | Z del modelo = cota relativa + 1,10 m. Correspondencia provisional con 286,10 m; no es cota de obra confirmada. | Contornos y sección documentados por el fabricante | 1 | 1 | Material: Hormigón HA-30
Cimentación de soporte de tuberías C36 · pedestal de hormigón | Parcela industrial Jinhong | Cimentación industrial | Cimentaciones de equipos y pedestales del fabricante · revisión recibida 04/09/2026 | 0.507098 | 0.507098 | 0.8 | 1.845 | 0.162 | process_plant | Zona de separación de aire | {"name":"Hormigón HA-30","status":"documentado","source":"Nota general de pedestales 2CED5"} | {"documented":[{"label":"Extensión local X","value":0.45,"unit":"m","source":"2CD0D, 2CD59, 2CD25, 2CDA1, 2CD17, 2CD19, 2CD7C, 2CEC6, 2CEA1","status":"derivada del contorno CAD"},{"label":"Extensión local Y","value":0.45,"unit":"m","source":"2CD0D, 2CD59, 2CD25, 2CDA1, 2CD17, 2CD19, 2CD7C, 2CEC6, 2CEA1","status":"derivada del contorno CAD"},{"label":"Cota inferior relativa adoptada","value":-0.6,"unit":"m","source":"ZD1 / DZ-1","status":"documentada"},{"label":"Cota superior relativa adoptada","value":0.2,"unit":"m","source":"ZD1 / DZ-1","status":"documentada / separación por material"}],"geometry":[{"label":"Extensión de la malla en X","value":0.5070979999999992,"unit":"m","source":"Geometría releída del IFC; datum absoluto de proceso provisional","status":"derivado"},{"label":"Extensión de la malla en Y","value":0.5070979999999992,"unit":"m","source":"Geometría releída del IFC; datum absoluto de proceso provisional","status":"derivado"},{"label":"Extensión de la malla en Z","value":0.8,"unit":"m","source":"Geometría releída del IFC; datum absoluto de proceso provisional","status":"derivado"},{"label":"Cota inferior de visualización","value":285.5,"unit":"m","source":"Geometría releída del IFC; datum absoluto de proceso provisional","status":"derivado"},{"label":"Cota superior de visualización","value":286.3,"unit":"m","source":"Geometría releída del IFC; datum absoluto de proceso provisional","status":"derivado"}]} | {"documentId":"LHD2609-JG00100-20260904","title":"Cimentaciones de equipos y pedestales del fabricante · revisión recibida 04/09/2026","date":"2026-09-04","sheet":"ZD1 / DZ-1","fileName":"LHD2609-JG00100_20260904.dwg","revisionCaveat":"Fecha de revisión tomada del nombre recibido; cajetines internos mantienen 02/07/2026 y algunos textos de plantilla.","sourceFileSha256":"b42eb027b7bc0b14c38d1d13514f4899b58a732aa8d0ba2ccf10fa2fc3192890"} | provisional | [] | {"Cota inferior relativa (m)":-0.6,"Cota superior relativa (m)":0.2,"Cero absoluto de visualización (m)":286.1,"Estado del cero absoluto":"Provisional","Criterio":"Las cotas relativas proceden del dibujo; la equivalencia absoluta no está confirmada."} | {"boundingBoxM":{"min":[59.370789,43.498823,0.5],"max":[59.877887,44.005921,1.3]},"extentsM":[0.507098,0.507098,0.8],"meshSurfaceM2":1.844999,"meshVolumeM3":0.162,"closedSolid":true,"basis":"Magnitudes de las mallas representadas, no cantidades certificadas de obra, compra o fabricación. Las partes pueden compartir superficies; no se suman como un despiece de materiales."} | {"profileId":"concrete_ha30","name":"Hormigón HA-30","materialName":"Hormigón HA-30","physicalMaterialStatus":"documentado","physicalMaterialSource":"Nota general de pedestales 2CED5","appearanceStatus":"criterio_visual","appearanceBasis":"Interpretación visual del material documental; el acabado, tono y parámetros PBR no son una especificación contractual.","note":"La apariencia gráfica no modifica ni confirma la especificación física del material."} | {"elementId":"found_0904_0e9acd518c15bc","ifcGuid":"1xfjUrWi9Jkhv2wB96rJzV","ifcClass":"IfcFooting","buildingId":"process_plant","buildingName":"Zona de separación de aire","sourceDocumentId":"LHD2609-JG00100-20260904","sourceRepresentationKind":"foundation"} | {"layerId":"foundations","layerName":"Cimentaciones","role":"Cimentación industrial","basis":"Clasificación por función del elemento; no modifica las especificaciones documentales."} | {"profileId":"concrete_ha30","name":"Hormigón HA-30","status":"criterio_visual","basis":"Interpretación visual del material documental; el acabado, tono y parámetros PBR no son una especificación contractual.","physicalMaterialUnchanged":true} | 0.162 | Hormigón HA-30 | Hormigón HA-30 | found_0904_0e9acd518c15bc | Nota general de pedestales 2CED5 | documentado | concrete_ha30 | [0.658824,0.658824,0.623529] | 0.94 | Zona de separación de aire; BIM · Cimentaciones | 0.507098 | 0.507098 | 0.8 | 285.5 | 286.3 | SUP-C36 | [] | ["C36"] | ZD1 / DZ-1 | ["2CD0D","2CD59","2CD25","2CDA1","2CD17","2CD19","2CD7C","2CEC6","2CEA1"] | SUP-C36/Cimentación de soporte de tuberías C36 · pedestal de hormigón | foundation | Geometría de fabricante; implantación absoluta provisional |  | Cimentaciones de equipos y pedestales del fabricante · revisión recibida 04/09/2026 | 2CD0D, 2CD59, 2CD25, 2CDA1, 2CD17, 2CD19, 2CD7C, 2CEC6, 2CEA1 | -0.6 | 0.2 | 0.2025 | Cotas relativas del dibujo. La equivalencia con un datum absoluto está pendiente. | Z del modelo = cota relativa + 1,10 m. Correspondencia provisional con 286,10 m; no es cota de obra confirmada. | Contornos y sección documentados por el fabricante | 0.45 | 0.45 | Material: Hormigón HA-30
Cimentación de soporte de tuberías C37 · cuerpo de hormigón | Parcela industrial Jinhong | Cimentación industrial | Cimentaciones de equipos y pedestales del fabricante · revisión recibida 04/09/2026 | 1.12688 | 1.12688 | 0.4 | 3.6 | 0.4 | process_plant | Zona de separación de aire | {"name":"Hormigón HA-30","status":"documentado","source":"Nota general de pedestales 2CED5"} | {"documented":[{"label":"Extensión local X","value":1.0,"unit":"m","source":"2CD0E, 2CD5A, 2CD26, 2CDA2, 2CD21, 2CD1C, 2CD7D, 2CEC7, 2CEA2","status":"derivada del contorno CAD"},{"label":"Extensión local Y","value":1.0,"unit":"m","source":"2CD0E, 2CD5A, 2CD26, 2CDA2, 2CD21, 2CD1C, 2CD7D, 2CEC7, 2CEA2","status":"derivada del contorno CAD"},{"label":"Cota inferior relativa adoptada","value":-1.0,"unit":"m","source":"ZD1 / DZ-1","status":"documentada"},{"label":"Cota superior relativa adoptada","value":-0.6,"unit":"m","source":"ZD1 / DZ-1","status":"documentada / separación por material"}],"geometry":[{"label":"Extensión de la malla en X","value":1.1268849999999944,"unit":"m","source":"Geometría releída del IFC; datum absoluto de proceso provisional","status":"derivado"},{"label":"Extensión de la malla en Y","value":1.1268849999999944,"unit":"m","source":"Geometría releída del IFC; datum absoluto de proceso provisional","status":"derivado"},{"label":"Extensión de la malla en Z","value":0.4,"unit":"m","source":"Geometría releída del IFC; datum absoluto de proceso provisional","status":"derivado"},{"label":"Cota inferior de visualización","value":285.1,"unit":"m","source":"Geometría releída del IFC; datum absoluto de proceso provisional","status":"derivado"},{"label":"Cota superior de visualización","value":285.5,"unit":"m","source":"Geometría releída del IFC; datum absoluto de proceso provisional","status":"derivado"}]} | {"documentId":"LHD2609-JG00100-20260904","title":"Cimentaciones de equipos y pedestales del fabricante · revisión recibida 04/09/2026","date":"2026-09-04","sheet":"ZD1 / DZ-1","fileName":"LHD2609-JG00100_20260904.dwg","revisionCaveat":"Fecha de revisión tomada del nombre recibido; cajetines internos mantienen 02/07/2026 y algunos textos de plantilla.","sourceFileSha256":"b42eb027b7bc0b14c38d1d13514f4899b58a732aa8d0ba2ccf10fa2fc3192890"} | provisional | [] | {"Cota inferior relativa (m)":-1.0,"Cota superior relativa (m)":-0.6,"Cero absoluto de visualización (m)":286.1,"Estado del cero absoluto":"Provisional","Criterio":"Las cotas relativas proceden del dibujo; la equivalencia absoluta no está confirmada."} | {"boundingBoxM":{"min":[60.645985,42.971003,0.1],"max":[61.77287,44.097888,0.5]},"extentsM":[1.126885,1.126885,0.4],"meshSurfaceM2":3.600001,"meshVolumeM3":0.4,"closedSolid":true,"basis":"Magnitudes de las mallas representadas, no cantidades certificadas de obra, compra o fabricación. Las partes pueden compartir superficies; no se suman como un despiece de materiales."} | {"profileId":"concrete_ha30","name":"Hormigón HA-30","materialName":"Hormigón HA-30","physicalMaterialStatus":"documentado","physicalMaterialSource":"Nota general de pedestales 2CED5","appearanceStatus":"criterio_visual","appearanceBasis":"Interpretación visual del material documental; el acabado, tono y parámetros PBR no son una especificación contractual.","note":"La apariencia gráfica no modifica ni confirma la especificación física del material."} | {"elementId":"found_0904_e931b10f19ccca","ifcGuid":"3n9lYkptzLHezbEwuMu3hh","ifcClass":"IfcFooting","buildingId":"process_plant","buildingName":"Zona de separación de aire","sourceDocumentId":"LHD2609-JG00100-20260904","sourceRepresentationKind":"foundation"} | {"layerId":"foundations","layerName":"Cimentaciones","role":"Cimentación industrial","basis":"Clasificación por función del elemento; no modifica las especificaciones documentales."} | {"profileId":"concrete_ha30","name":"Hormigón HA-30","status":"criterio_visual","basis":"Interpretación visual del material documental; el acabado, tono y parámetros PBR no son una especificación contractual.","physicalMaterialUnchanged":true} | 0.4 | Hormigón HA-30 | Hormigón HA-30 | found_0904_e931b10f19ccca | Nota general de pedestales 2CED5 | documentado | concrete_ha30 | [0.658824,0.658824,0.623529] | 0.94 | Zona de separación de aire; BIM · Cimentaciones | 1.12688 | 1.12688 | 0.4 | 285.1 | 285.5 | SUP-C37 | [] | ["C37"] | ZD1 / DZ-1 | ["2CD0E","2CD5A","2CD26","2CDA2","2CD21","2CD1C","2CD7D","2CEC7","2CEA2"] | SUP-C37/Cimentación de soporte de tuberías C37 · cuerpo de hormigón | foundation | Geometría de fabricante; implantación absoluta provisional |  | Cimentaciones de equipos y pedestales del fabricante · revisión recibida 04/09/2026 | 2CD0E, 2CD5A, 2CD26, 2CDA2, 2CD21, 2CD1C, 2CD7D, 2CEC7, 2CEA2 | -1 | -0.6 | 1 | Cotas relativas del dibujo. La equivalencia con un datum absoluto está pendiente. | Z del modelo = cota relativa + 1,10 m. Correspondencia provisional con 286,10 m; no es cota de obra confirmada. | Contornos y sección documentados por el fabricante | 1 | 1 | Material: Hormigón HA-30
Cimentación de soporte de tuberías C37 · pedestal de hormigón | Parcela industrial Jinhong | Cimentación industrial | Cimentaciones de equipos y pedestales del fabricante · revisión recibida 04/09/2026 | 0.507098 | 0.507098 | 0.8 | 1.845 | 0.162 | process_plant | Zona de separación de aire | {"name":"Hormigón HA-30","status":"documentado","source":"Nota general de pedestales 2CED5"} | {"documented":[{"label":"Extensión local X","value":0.45,"unit":"m","source":"2CD0E, 2CD5A, 2CD26, 2CDA2, 2CD21, 2CD1C, 2CD7D, 2CEC7, 2CEA2","status":"derivada del contorno CAD"},{"label":"Extensión local Y","value":0.45,"unit":"m","source":"2CD0E, 2CD5A, 2CD26, 2CDA2, 2CD21, 2CD1C, 2CD7D, 2CEC7, 2CEA2","status":"derivada del contorno CAD"},{"label":"Cota inferior relativa adoptada","value":-0.6,"unit":"m","source":"ZD1 / DZ-1","status":"documentada"},{"label":"Cota superior relativa adoptada","value":0.2,"unit":"m","source":"ZD1 / DZ-1","status":"documentada / separación por material"}],"geometry":[{"label":"Extensión de la malla en X","value":0.5070979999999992,"unit":"m","source":"Geometría releída del IFC; datum absoluto de proceso provisional","status":"derivado"},{"label":"Extensión de la malla en Y","value":0.5070979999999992,"unit":"m","source":"Geometría releída del IFC; datum absoluto de proceso provisional","status":"derivado"},{"label":"Extensión de la malla en Z","value":0.8,"unit":"m","source":"Geometría releída del IFC; datum absoluto de proceso provisional","status":"derivado"},{"label":"Cota inferior de visualización","value":285.5,"unit":"m","source":"Geometría releída del IFC; datum absoluto de proceso provisional","status":"derivado"},{"label":"Cota superior de visualización","value":286.3,"unit":"m","source":"Geometría releída del IFC; datum absoluto de proceso provisional","status":"derivado"}]} | {"documentId":"LHD2609-JG00100-20260904","title":"Cimentaciones de equipos y pedestales del fabricante · revisión recibida 04/09/2026","date":"2026-09-04","sheet":"ZD1 / DZ-1","fileName":"LHD2609-JG00100_20260904.dwg","revisionCaveat":"Fecha de revisión tomada del nombre recibido; cajetines internos mantienen 02/07/2026 y algunos textos de plantilla.","sourceFileSha256":"b42eb027b7bc0b14c38d1d13514f4899b58a732aa8d0ba2ccf10fa2fc3192890"} | provisional | [] | {"Cota inferior relativa (m)":-0.6,"Cota superior relativa (m)":0.2,"Cero absoluto de visualización (m)":286.1,"Estado del cero absoluto":"Provisional","Criterio":"Las cotas relativas proceden del dibujo; la equivalencia absoluta no está confirmada."} | {"boundingBoxM":{"min":[60.955878,43.280896,0.5],"max":[61.462976,43.787994,1.3]},"extentsM":[0.507098,0.507098,0.8],"meshSurfaceM2":1.844999,"meshVolumeM3":0.162,"closedSolid":true,"basis":"Magnitudes de las mallas representadas, no cantidades certificadas de obra, compra o fabricación. Las partes pueden compartir superficies; no se suman como un despiece de materiales."} | {"profileId":"concrete_ha30","name":"Hormigón HA-30","materialName":"Hormigón HA-30","physicalMaterialStatus":"documentado","physicalMaterialSource":"Nota general de pedestales 2CED5","appearanceStatus":"criterio_visual","appearanceBasis":"Interpretación visual del material documental; el acabado, tono y parámetros PBR no son una especificación contractual.","note":"La apariencia gráfica no modifica ni confirma la especificación física del material."} | {"elementId":"found_0904_13ef60eea62ff5","ifcGuid":"1n7ux6xavMnB1OIuPL8vXR","ifcClass":"IfcFooting","buildingId":"process_plant","buildingName":"Zona de separación de aire","sourceDocumentId":"LHD2609-JG00100-20260904","sourceRepresentationKind":"foundation"} | {"layerId":"foundations","layerName":"Cimentaciones","role":"Cimentación industrial","basis":"Clasificación por función del elemento; no modifica las especificaciones documentales."} | {"profileId":"concrete_ha30","name":"Hormigón HA-30","status":"criterio_visual","basis":"Interpretación visual del material documental; el acabado, tono y parámetros PBR no son una especificación contractual.","physicalMaterialUnchanged":true} | 0.162 | Hormigón HA-30 | Hormigón HA-30 | found_0904_13ef60eea62ff5 | Nota general de pedestales 2CED5 | documentado | concrete_ha30 | [0.658824,0.658824,0.623529] | 0.94 | Zona de separación de aire; BIM · Cimentaciones | 0.507098 | 0.507098 | 0.8 | 285.5 | 286.3 | SUP-C37 | [] | ["C37"] | ZD1 / DZ-1 | ["2CD0E","2CD5A","2CD26","2CDA2","2CD21","2CD1C","2CD7D","2CEC7","2CEA2"] | SUP-C37/Cimentación de soporte de tuberías C37 · pedestal de hormigón | foundation | Geometría de fabricante; implantación absoluta provisional |  | Cimentaciones de equipos y pedestales del fabricante · revisión recibida 04/09/2026 | 2CD0E, 2CD5A, 2CD26, 2CDA2, 2CD21, 2CD1C, 2CD7D, 2CEC7, 2CEA2 | -0.6 | 0.2 | 0.2025 | Cotas relativas del dibujo. La equivalencia con un datum absoluto está pendiente. | Z del modelo = cota relativa + 1,10 m. Correspondencia provisional con 286,10 m; no es cota de obra confirmada. | Contornos y sección documentados por el fabricante | 0.45 | 0.45 | Material: Hormigón HA-30
Cimentación de soporte de tuberías C38 · cuerpo de hormigón | Parcela industrial Jinhong | Cimentación industrial | Cimentaciones de equipos y pedestales del fabricante · revisión recibida 04/09/2026 | 1.12689 | 1.12689 | 0.4 | 3.6 | 0.4 | process_plant | Zona de separación de aire | {"name":"Hormigón HA-30","status":"documentado","source":"Nota general de pedestales 2CED5"} | {"documented":[{"label":"Extensión local X","value":1.0,"unit":"m","source":"2CD0F, 2CD5B, 2CD27, 2CDA3, 2CD1F, 2CD20, 2CD7E, 2CEC8, 2CEA3","status":"derivada del contorno CAD"},{"label":"Extensión local Y","value":1.0,"unit":"m","source":"2CD0F, 2CD5B, 2CD27, 2CDA3, 2CD1F, 2CD20, 2CD7E, 2CEC8, 2CEA3","status":"derivada del contorno CAD"},{"label":"Cota inferior relativa adoptada","value":-1.0,"unit":"m","source":"ZD1 / DZ-1","status":"documentada"},{"label":"Cota superior relativa adoptada","value":-0.6,"unit":"m","source":"ZD1 / DZ-1","status":"documentada / separación por material"}],"geometry":[{"label":"Extensión de la malla en X","value":1.1268850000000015,"unit":"m","source":"Geometría releída del IFC; datum absoluto de proceso provisional","status":"derivado"},{"label":"Extensión de la malla en Y","value":1.1268850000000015,"unit":"m","source":"Geometría releída del IFC; datum absoluto de proceso provisional","status":"derivado"},{"label":"Extensión de la malla en Z","value":0.4,"unit":"m","source":"Geometría releída del IFC; datum absoluto de proceso provisional","status":"derivado"},{"label":"Cota inferior de visualización","value":285.1,"unit":"m","source":"Geometría releída del IFC; datum absoluto de proceso provisional","status":"derivado"},{"label":"Cota superior de visualización","value":285.5,"unit":"m","source":"Geometría releída del IFC; datum absoluto de proceso provisional","status":"derivado"}]} | {"documentId":"LHD2609-JG00100-20260904","title":"Cimentaciones de equipos y pedestales del fabricante · revisión recibida 04/09/2026","date":"2026-09-04","sheet":"ZD1 / DZ-1","fileName":"LHD2609-JG00100_20260904.dwg","revisionCaveat":"Fecha de revisión tomada del nombre recibido; cajetines internos mantienen 02/07/2026 y algunos textos de plantilla.","sourceFileSha256":"b42eb027b7bc0b14c38d1d13514f4899b58a732aa8d0ba2ccf10fa2fc3192890"} | provisional | [] | {"Cota inferior relativa (m)":-1.0,"Cota superior relativa (m)":-0.6,"Cero absoluto de visualización (m)":286.1,"Estado del cero absoluto":"Provisional","Criterio":"Las cotas relativas proceden del dibujo; la equivalencia absoluta no está confirmada."} | {"boundingBoxM":{"min":[58.693145,40.514091,0.1],"max":[59.82003,41.640976,0.5]},"extentsM":[1.126885,1.126885,0.4],"meshSurfaceM2":3.600001,"meshVolumeM3":0.4,"closedSolid":true,"basis":"Magnitudes de las mallas representadas, no cantidades certificadas de obra, compra o fabricación. Las partes pueden compartir superficies; no se suman como un despiece de materiales."} | {"profileId":"concrete_ha30","name":"Hormigón HA-30","materialName":"Hormigón HA-30","physicalMaterialStatus":"documentado","physicalMaterialSource":"Nota general de pedestales 2CED5","appearanceStatus":"criterio_visual","appearanceBasis":"Interpretación visual del material documental; el acabado, tono y parámetros PBR no son una especificación contractual.","note":"La apariencia gráfica no modifica ni confirma la especificación física del material."} | {"elementId":"found_0904_313d1b838a2f34","ifcGuid":"2UOkDErlbNDgq6MQE5Ktc5","ifcClass":"IfcFooting","buildingId":"process_plant","buildingName":"Zona de separación de aire","sourceDocumentId":"LHD2609-JG00100-20260904","sourceRepresentationKind":"foundation"} | {"layerId":"foundations","layerName":"Cimentaciones","role":"Cimentación industrial","basis":"Clasificación por función del elemento; no modifica las especificaciones documentales."} | {"profileId":"concrete_ha30","name":"Hormigón HA-30","status":"criterio_visual","basis":"Interpretación visual del material documental; el acabado, tono y parámetros PBR no son una especificación contractual.","physicalMaterialUnchanged":true} | 0.4 | Hormigón HA-30 | Hormigón HA-30 | found_0904_313d1b838a2f34 | Nota general de pedestales 2CED5 | documentado | concrete_ha30 | [0.658824,0.658824,0.623529] | 0.94 | Zona de separación de aire; BIM · Cimentaciones | 1.12689 | 1.12689 | 0.4 | 285.1 | 285.5 | SUP-C38 | [] | ["C38"] | ZD1 / DZ-1 | ["2CD0F","2CD5B","2CD27","2CDA3","2CD1F","2CD20","2CD7E","2CEC8","2CEA3"] | SUP-C38/Cimentación de soporte de tuberías C38 · cuerpo de hormigón | foundation | Geometría de fabricante; implantación absoluta provisional |  | Cimentaciones de equipos y pedestales del fabricante · revisión recibida 04/09/2026 | 2CD0F, 2CD5B, 2CD27, 2CDA3, 2CD1F, 2CD20, 2CD7E, 2CEC8, 2CEA3 | -1 | -0.6 | 1 | Cotas relativas del dibujo. La equivalencia con un datum absoluto está pendiente. | Z del modelo = cota relativa + 1,10 m. Correspondencia provisional con 286,10 m; no es cota de obra confirmada. | Contornos y sección documentados por el fabricante | 1 | 1 | Material: Hormigón HA-30
Cimentación de soporte de tuberías C38 · pedestal de hormigón | Parcela industrial Jinhong | Cimentación industrial | Cimentaciones de equipos y pedestales del fabricante · revisión recibida 04/09/2026 | 0.507098 | 0.507098 | 0.8 | 1.845 | 0.162 | process_plant | Zona de separación de aire | {"name":"Hormigón HA-30","status":"documentado","source":"Nota general de pedestales 2CED5"} | {"documented":[{"label":"Extensión local X","value":0.45,"unit":"m","source":"2CD0F, 2CD5B, 2CD27, 2CDA3, 2CD1F, 2CD20, 2CD7E, 2CEC8, 2CEA3","status":"derivada del contorno CAD"},{"label":"Extensión local Y","value":0.45,"unit":"m","source":"2CD0F, 2CD5B, 2CD27, 2CDA3, 2CD1F, 2CD20, 2CD7E, 2CEC8, 2CEA3","status":"derivada del contorno CAD"},{"label":"Cota inferior relativa adoptada","value":-0.6,"unit":"m","source":"ZD1 / DZ-1","status":"documentada"},{"label":"Cota superior relativa adoptada","value":0.2,"unit":"m","source":"ZD1 / DZ-1","status":"documentada / separación por material"}],"geometry":[{"label":"Extensión de la malla en X","value":0.5070980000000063,"unit":"m","source":"Geometría releída del IFC; datum absoluto de proceso provisional","status":"derivado"},{"label":"Extensión de la malla en Y","value":0.5070979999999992,"unit":"m","source":"Geometría releída del IFC; datum absoluto de proceso provisional","status":"derivado"},{"label":"Extensión de la malla en Z","value":0.8,"unit":"m","source":"Geometría releída del IFC; datum absoluto de proceso provisional","status":"derivado"},{"label":"Cota inferior de visualización","value":285.5,"unit":"m","source":"Geometría releída del IFC; datum absoluto de proceso provisional","status":"derivado"},{"label":"Cota superior de visualización","value":286.3,"unit":"m","source":"Geometría releída del IFC; datum absoluto de proceso provisional","status":"derivado"}]} | {"documentId":"LHD2609-JG00100-20260904","title":"Cimentaciones de equipos y pedestales del fabricante · revisión recibida 04/09/2026","date":"2026-09-04","sheet":"ZD1 / DZ-1","fileName":"LHD2609-JG00100_20260904.dwg","revisionCaveat":"Fecha de revisión tomada del nombre recibido; cajetines internos mantienen 02/07/2026 y algunos textos de plantilla.","sourceFileSha256":"b42eb027b7bc0b14c38d1d13514f4899b58a732aa8d0ba2ccf10fa2fc3192890"} | provisional | [] | {"Cota inferior relativa (m)":-0.6,"Cota superior relativa (m)":0.2,"Cero absoluto de visualización (m)":286.1,"Estado del cero absoluto":"Provisional","Criterio":"Las cotas relativas proceden del dibujo; la equivalencia absoluta no está confirmada."} | {"boundingBoxM":{"min":[59.003038,40.823984,0.5],"max":[59.510136,41.331082,1.3]},"extentsM":[0.507098,0.507098,0.8],"meshSurfaceM2":1.845,"meshVolumeM3":0.162,"closedSolid":true,"basis":"Magnitudes de las mallas representadas, no cantidades certificadas de obra, compra o fabricación. Las partes pueden compartir superficies; no se suman como un despiece de materiales."} | {"profileId":"concrete_ha30","name":"Hormigón HA-30","materialName":"Hormigón HA-30","physicalMaterialStatus":"documentado","physicalMaterialSource":"Nota general de pedestales 2CED5","appearanceStatus":"criterio_visual","appearanceBasis":"Interpretación visual del material documental; el acabado, tono y parámetros PBR no son una especificación contractual.","note":"La apariencia gráfica no modifica ni confirma la especificación física del material."} | {"elementId":"found_0904_2355188b89180e","ifcGuid":"1jl8x_eWzVJedlrqb1F8QG","ifcClass":"IfcFooting","buildingId":"process_plant","buildingName":"Zona de separación de aire","sourceDocumentId":"LHD2609-JG00100-20260904","sourceRepresentationKind":"foundation"} | {"layerId":"foundations","layerName":"Cimentaciones","role":"Cimentación industrial","basis":"Clasificación por función del elemento; no modifica las especificaciones documentales."} | {"profileId":"concrete_ha30","name":"Hormigón HA-30","status":"criterio_visual","basis":"Interpretación visual del material documental; el acabado, tono y parámetros PBR no son una especificación contractual.","physicalMaterialUnchanged":true} | 0.162 | Hormigón HA-30 | Hormigón HA-30 | found_0904_2355188b89180e | Nota general de pedestales 2CED5 | documentado | concrete_ha30 | [0.658824,0.658824,0.623529] | 0.94 | Zona de separación de aire; BIM · Cimentaciones | 0.507098 | 0.507098 | 0.8 | 285.5 | 286.3 | SUP-C38 | [] | ["C38"] | ZD1 / DZ-1 | ["2CD0F","2CD5B","2CD27","2CDA3","2CD1F","2CD20","2CD7E","2CEC8","2CEA3"] | SUP-C38/Cimentación de soporte de tuberías C38 · pedestal de hormigón | foundation | Geometría de fabricante; implantación absoluta provisional |  | Cimentaciones de equipos y pedestales del fabricante · revisión recibida 04/09/2026 | 2CD0F, 2CD5B, 2CD27, 2CDA3, 2CD1F, 2CD20, 2CD7E, 2CEC8, 2CEA3 | -0.6 | 0.2 | 0.2025 | Cotas relativas del dibujo. La equivalencia con un datum absoluto está pendiente. | Z del modelo = cota relativa + 1,10 m. Correspondencia provisional con 286,10 m; no es cota de obra confirmada. | Contornos y sección documentados por el fabricante | 0.45 | 0.45 | Material: Hormigón HA-30
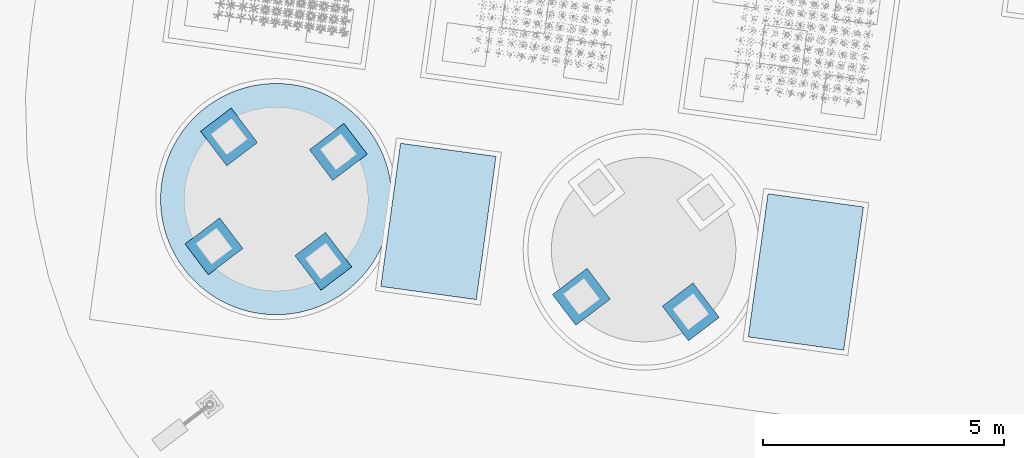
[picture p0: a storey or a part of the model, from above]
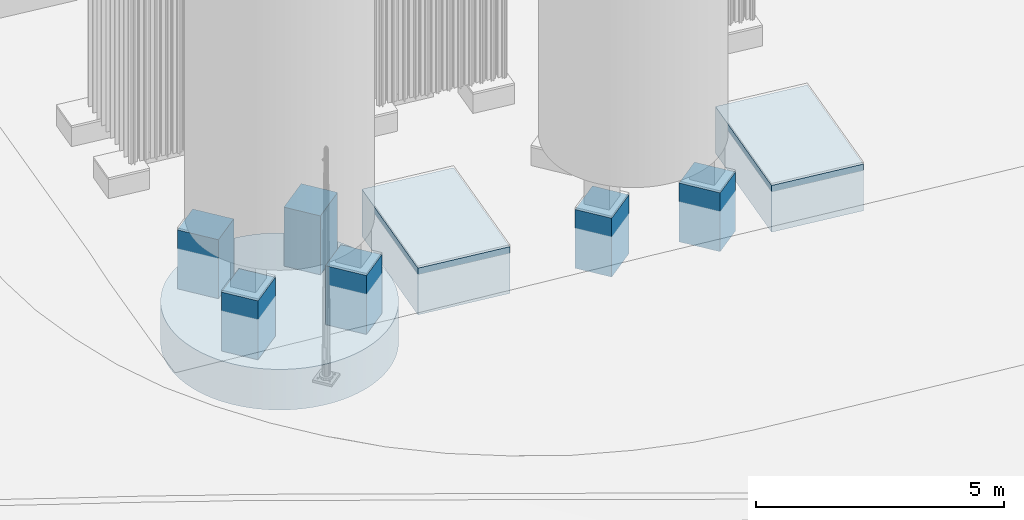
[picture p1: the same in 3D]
Properties of the parts of a building model (IFC4), part 85 of 134

# IfcFooting (214)
Name | In | Description = category = Categoria = Funcion | Document | ExtensionX (m) | ExtensionY (m) | ExtensionZ (m) | SuperficieDeLaMalla (m2) | VolumenGeometrico (m3) | buildingId | buildingName | material | dimensions | JH_InformacionBIM, source = DocumentoFuente | JH_InformacionBIM, status = EstadoDeInformacion | issues = IncidenciasPendientes | positioning = PosicionYEstado | geometryMetrics | materialAppearance | visualizationIdentity | classification | appearance | Volumen geométrico (m³) | JH_Trazabilidad, Material = name | Acabado de visualización = Acabado | Identificador | JH_EvidenciaDeMaterial, source | JH_EvidenciaDeMaterial, status | Perfil | ColorRGB | Rugosidad | Group | Extensión de la malla en X (m) | Extensión de la malla en Y (m) | Extensión de la malla en Z (m) = Espesor o altura real de sección (m) | Cota inferior de visualización (m) | Cota superior de visualización (m) | assemblyId = Conjunto de cimentación | equipmentIds | supportPositionIds | sectionRef = Sección de referencia | sourceCadHandles | stableElementKey | representationKind | geometryStatus | Equipos asociados | Documento de origen | Identificadores CAD de referencia | Cota inferior relativa (m) = Cota inferior relativa adoptada (m) | Cota superior relativa (m) = Cota superior relativa adoptada (m) | Área de planta (m²) | Referencia vertical | Implantación para visualización | Estado de la geometría | Extensión local X (m) | Extensión local Y (m) | Incidencias de origen
Cimentación de soporte de tuberías C39 · cuerpo de hormigón | Parcela industrial Jinhong | Cimentación industrial | Cimentaciones de equipos y pedestales del fabricante · revisión recibida 04/09/2026 | 1.12689 | 1.12689 | 0.4 | 3.6 | 0.4 | process_plant | Zona de separación de aire | {"name":"Hormigón HA-30","status":"documentado","source":"Nota general de pedestales 2CED5"} | {"documented":[{"label":"Extensión local X","value":1.0,"unit":"m","source":"2CD10, 2CD5C, 2CD28, 2CDA4, 2CD1D, 2CD1E, 2CD7F, 2CEC9, 2CEA4","status":"derivada del contorno CAD"},{"label":"Extensión local Y","value":1.0,"unit":"m","source":"2CD10, 2CD5C, 2CD28, 2CDA4, 2CD1D, 2CD1E, 2CD7F, 2CEC9, 2CEA4","status":"derivada del contorno CAD"},{"label":"Cota inferior relativa adoptada","value":-1.0,"unit":"m","source":"ZD1 / DZ-1","status":"documentada"},{"label":"Cota superior relativa adoptada","value":-0.6,"unit":"m","source":"ZD1 / DZ-1","status":"documentada / separación por material"}],"geometry":[{"label":"Extensión de la malla en X","value":1.1268850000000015,"unit":"m","source":"Geometría releída del IFC; datum absoluto de proceso provisional","status":"derivado"},{"label":"Extensión de la malla en Y","value":1.1268850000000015,"unit":"m","source":"Geometría releída del IFC; datum absoluto de proceso provisional","status":"derivado"},{"label":"Extensión de la malla en Z","value":0.4,"unit":"m","source":"Geometría releída del IFC; datum absoluto de proceso provisional","status":"derivado"},{"label":"Cota inferior de visualización","value":285.1,"unit":"m","source":"Geometría releída del IFC; datum absoluto de proceso provisional","status":"derivado"},{"label":"Cota superior de visualización","value":285.5,"unit":"m","source":"Geometría releída del IFC; datum absoluto de proceso provisional","status":"derivado"}]} | {"documentId":"LHD2609-JG00100-20260904","title":"Cimentaciones de equipos y pedestales del fabricante · revisión recibida 04/09/2026","date":"2026-09-04","sheet":"ZD1 / DZ-1","fileName":"LHD2609-JG00100_20260904.dwg","revisionCaveat":"Fecha de revisión tomada del nombre recibido; cajetines internos mantienen 02/07/2026 y algunos textos de plantilla.","sourceFileSha256":"b42eb027b7bc0b14c38d1d13514f4899b58a732aa8d0ba2ccf10fa2fc3192890"} | provisional | [] | {"Cota inferior relativa (m)":-1.0,"Cota superior relativa (m)":-0.6,"Cero absoluto de visualización (m)":286.1,"Estado del cero absoluto":"Provisional","Criterio":"Las cotas relativas proceden del dibujo; la equivalencia absoluta no está confirmada."} | {"boundingBoxM":{"min":[60.278234,40.296165,0.1],"max":[61.405119,41.42305,0.5]},"extentsM":[1.126885,1.126885,0.4],"meshSurfaceM2":3.600001,"meshVolumeM3":0.4,"closedSolid":true,"basis":"Magnitudes de las mallas representadas, no cantidades certificadas de obra, compra o fabricación. Las partes pueden compartir superficies; no se suman como un despiece de materiales."} | {"profileId":"concrete_ha30","name":"Hormigón HA-30","materialName":"Hormigón HA-30","physicalMaterialStatus":"documentado","physicalMaterialSource":"Nota general de pedestales 2CED5","appearanceStatus":"criterio_visual","appearanceBasis":"Interpretación visual del material documental; el acabado, tono y parámetros PBR no son una especificación contractual.","note":"La apariencia gráfica no modifica ni confirma la especificación física del material."} | {"elementId":"found_0904_ffe59bc8387008","ifcGuid":"1oOmBjHP5NSOaRfngldywp","ifcClass":"IfcFooting","buildingId":"process_plant","buildingName":"Zona de separación de aire","sourceDocumentId":"LHD2609-JG00100-20260904","sourceRepresentationKind":"foundation"} | {"layerId":"foundations","layerName":"Cimentaciones","role":"Cimentación industrial","basis":"Clasificación por función del elemento; no modifica las especificaciones documentales."} | {"profileId":"concrete_ha30","name":"Hormigón HA-30","status":"criterio_visual","basis":"Interpretación visual del material documental; el acabado, tono y parámetros PBR no son una especificación contractual.","physicalMaterialUnchanged":true} | 0.4 | Hormigón HA-30 | Hormigón HA-30 | found_0904_ffe59bc8387008 | Nota general de pedestales 2CED5 | documentado | concrete_ha30 | [0.658824,0.658824,0.623529] | 0.94 | Zona de separación de aire; BIM · Cimentaciones | 1.12689 | 1.12689 | 0.4 | 285.1 | 285.5 | SUP-C39 | [] | ["C39"] | ZD1 / DZ-1 | ["2CD10","2CD5C","2CD28","2CDA4","2CD1D","2CD1E","2CD7F","2CEC9","2CEA4"] | SUP-C39/Cimentación de soporte de tuberías C39 · cuerpo de hormigón | foundation | Geometría de fabricante; implantación absoluta provisional |  | Cimentaciones de equipos y pedestales del fabricante · revisión recibida 04/09/2026 | 2CD10, 2CD5C, 2CD28, 2CDA4, 2CD1D, 2CD1E, 2CD7F, 2CEC9, 2CEA4 | -1 | -0.6 | 1 | Cotas relativas del dibujo. La equivalencia con un datum absoluto está pendiente. | Z del modelo = cota relativa + 1,10 m. Correspondencia provisional con 286,10 m; no es cota de obra confirmada. | Contornos y sección documentados por el fabricante | 1 | 1 | Material: Hormigón HA-30
Cimentación de soporte de tuberías C39 · pedestal de hormigón | Parcela industrial Jinhong | Cimentación industrial | Cimentaciones de equipos y pedestales del fabricante · revisión recibida 04/09/2026 | 0.507099 | 0.507098 | 0.8 | 1.845 | 0.162 | process_plant | Zona de separación de aire | {"name":"Hormigón HA-30","status":"documentado","source":"Nota general de pedestales 2CED5"} | {"documented":[{"label":"Extensión local X","value":0.45,"unit":"m","source":"2CD10, 2CD5C, 2CD28, 2CDA4, 2CD1D, 2CD1E, 2CD7F, 2CEC9, 2CEA4","status":"derivada del contorno CAD"},{"label":"Extensión local Y","value":0.45,"unit":"m","source":"2CD10, 2CD5C, 2CD28, 2CDA4, 2CD1D, 2CD1E, 2CD7F, 2CEC9, 2CEA4","status":"derivada del contorno CAD"},{"label":"Cota inferior relativa adoptada","value":-0.6,"unit":"m","source":"ZD1 / DZ-1","status":"documentada"},{"label":"Cota superior relativa adoptada","value":0.2,"unit":"m","source":"ZD1 / DZ-1","status":"documentada / separación por material"}],"geometry":[{"label":"Extensión de la malla en X","value":0.5070989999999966,"unit":"m","source":"Geometría releída del IFC; datum absoluto de proceso provisional","status":"derivado"},{"label":"Extensión de la malla en Y","value":0.5070979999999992,"unit":"m","source":"Geometría releída del IFC; datum absoluto de proceso provisional","status":"derivado"},{"label":"Extensión de la malla en Z","value":0.8,"unit":"m","source":"Geometría releída del IFC; datum absoluto de proceso provisional","status":"derivado"},{"label":"Cota inferior de visualización","value":285.5,"unit":"m","source":"Geometría releída del IFC; datum absoluto de proceso provisional","status":"derivado"},{"label":"Cota superior de visualización","value":286.3,"unit":"m","source":"Geometría releída del IFC; datum absoluto de proceso provisional","status":"derivado"}]} | {"documentId":"LHD2609-JG00100-20260904","title":"Cimentaciones de equipos y pedestales del fabricante · revisión recibida 04/09/2026","date":"2026-09-04","sheet":"ZD1 / DZ-1","fileName":"LHD2609-JG00100_20260904.dwg","revisionCaveat":"Fecha de revisión tomada del nombre recibido; cajetines internos mantienen 02/07/2026 y algunos textos de plantilla.","sourceFileSha256":"b42eb027b7bc0b14c38d1d13514f4899b58a732aa8d0ba2ccf10fa2fc3192890"} | provisional | [] | {"Cota inferior relativa (m)":-0.6,"Cota superior relativa (m)":0.2,"Cero absoluto de visualización (m)":286.1,"Estado del cero absoluto":"Provisional","Criterio":"Las cotas relativas proceden del dibujo; la equivalencia absoluta no está confirmada."} | {"boundingBoxM":{"min":[60.588127,40.606058,0.5],"max":[61.095226,41.113156,1.3]},"extentsM":[0.507099,0.507098,0.8],"meshSurfaceM2":1.845001,"meshVolumeM3":0.162,"closedSolid":true,"basis":"Magnitudes de las mallas representadas, no cantidades certificadas de obra, compra o fabricación. Las partes pueden compartir superficies; no se suman como un despiece de materiales."} | {"profileId":"concrete_ha30","name":"Hormigón HA-30","materialName":"Hormigón HA-30","physicalMaterialStatus":"documentado","physicalMaterialSource":"Nota general de pedestales 2CED5","appearanceStatus":"criterio_visual","appearanceBasis":"Interpretación visual del material documental; el acabado, tono y parámetros PBR no son una especificación contractual.","note":"La apariencia gráfica no modifica ni confirma la especificación física del material."} | {"elementId":"found_0904_7aad8027878d0a","ifcGuid":"3$74$lrL1M98N7kH6Mwub3","ifcClass":"IfcFooting","buildingId":"process_plant","buildingName":"Zona de separación de aire","sourceDocumentId":"LHD2609-JG00100-20260904","sourceRepresentationKind":"foundation"} | {"layerId":"foundations","layerName":"Cimentaciones","role":"Cimentación industrial","basis":"Clasificación por función del elemento; no modifica las especificaciones documentales."} | {"profileId":"concrete_ha30","name":"Hormigón HA-30","status":"criterio_visual","basis":"Interpretación visual del material documental; el acabado, tono y parámetros PBR no son una especificación contractual.","physicalMaterialUnchanged":true} | 0.162 | Hormigón HA-30 | Hormigón HA-30 | found_0904_7aad8027878d0a | Nota general de pedestales 2CED5 | documentado | concrete_ha30 | [0.658824,0.658824,0.623529] | 0.94 | Zona de separación de aire; BIM · Cimentaciones | 0.507099 | 0.507098 | 0.8 | 285.5 | 286.3 | SUP-C39 | [] | ["C39"] | ZD1 / DZ-1 | ["2CD10","2CD5C","2CD28","2CDA4","2CD1D","2CD1E","2CD7F","2CEC9","2CEA4"] | SUP-C39/Cimentación de soporte de tuberías C39 · pedestal de hormigón | foundation | Geometría de fabricante; implantación absoluta provisional |  | Cimentaciones de equipos y pedestales del fabricante · revisión recibida 04/09/2026 | 2CD10, 2CD5C, 2CD28, 2CDA4, 2CD1D, 2CD1E, 2CD7F, 2CEC9, 2CEA4 | -0.6 | 0.2 | 0.2025 | Cotas relativas del dibujo. La equivalencia con un datum absoluto está pendiente. | Z del modelo = cota relativa + 1,10 m. Correspondencia provisional con 286,10 m; no es cota de obra confirmada. | Contornos y sección documentados por el fabricante | 0.45 | 0.45 | Material: Hormigón HA-30
Cimentación de soporte de tuberías C40 · cuerpo de hormigón | Parcela industrial Jinhong | Cimentación industrial | Cimentaciones de equipos y pedestales del fabricante · revisión recibida 04/09/2026 | 1.12688 | 1.12688 | 0.4 | 3.6 | 0.4 | process_plant | Zona de separación de aire | {"name":"Hormigón HA-30","status":"documentado","source":"Nota general de pedestales 2CED5"} | {"documented":[{"label":"Extensión local X","value":1.0,"unit":"m","source":"2CD11, 2CD5D, 2CD29, 2CDA5, 2CD1A, 2CD1B, 2CD80, 2CECA, 2CEA5","status":"derivada del contorno CAD"},{"label":"Extensión local Y","value":1.0,"unit":"m","source":"2CD11, 2CD5D, 2CD29, 2CDA5, 2CD1A, 2CD1B, 2CD80, 2CECA, 2CEA5","status":"derivada del contorno CAD"},{"label":"Cota inferior relativa adoptada","value":-1.0,"unit":"m","source":"ZD1 / DZ-1","status":"interpretación con conflicto conservado"},{"label":"Cota superior relativa adoptada","value":-0.6,"unit":"m","source":"ZD1 / DZ-1","status":"documentada / separación por material"}],"geometry":[{"label":"Extensión de la malla en X","value":1.1268849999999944,"unit":"m","source":"Geometría releída del IFC; datum absoluto de proceso provisional","status":"derivado"},{"label":"Extensión de la malla en Y","value":1.126884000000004,"unit":"m","source":"Geometría releída del IFC; datum absoluto de proceso provisional","status":"derivado"},{"label":"Extensión de la malla en Z","value":0.4,"unit":"m","source":"Geometría releída del IFC; datum absoluto de proceso provisional","status":"derivado"},{"label":"Cota inferior de visualización","value":285.1,"unit":"m","source":"Geometría releída del IFC; datum absoluto de proceso provisional","status":"derivado"},{"label":"Cota superior de visualización","value":285.5,"unit":"m","source":"Geometría releída del IFC; datum absoluto de proceso provisional","status":"derivado"}]} | {"documentId":"LHD2609-JG00100-20260904","title":"Cimentaciones de equipos y pedestales del fabricante · revisión recibida 04/09/2026","date":"2026-09-04","sheet":"ZD1 / DZ-1","fileName":"LHD2609-JG00100_20260904.dwg","revisionCaveat":"Fecha de revisión tomada del nombre recibido; cajetines internos mantienen 02/07/2026 y algunos textos de plantilla.","sourceFileSha256":"b42eb027b7bc0b14c38d1d13514f4899b58a732aa8d0ba2ccf10fa2fc3192890"} | provisional | ["Identificador original HA-40 en columna de posición; C40 se infiere por secuencia. Se conserva el original y no se interpreta como material."] | {"Cota inferior relativa (m)":-1.0,"Cota superior relativa (m)":-0.6,"Cero absoluto de visualización (m)":286.1,"Estado del cero absoluto":"Provisional","Criterio":"Las cotas relativas proceden del dibujo; la equivalencia absoluta no está confirmada."} | {"boundingBoxM":{"min":[58.284533,37.542049,0.1],"max":[59.411418,38.668933,0.5]},"extentsM":[1.126885,1.126884,0.4],"meshSurfaceM2":3.599999,"meshVolumeM3":0.4,"closedSolid":true,"basis":"Magnitudes de las mallas representadas, no cantidades certificadas de obra, compra o fabricación. Las partes pueden compartir superficies; no se suman como un despiece de materiales."} | {"profileId":"concrete_ha30","name":"Hormigón HA-30","materialName":"Hormigón HA-30","physicalMaterialStatus":"documentado","physicalMaterialSource":"Nota general de pedestales 2CED5","appearanceStatus":"criterio_visual","appearanceBasis":"Interpretación visual del material documental; el acabado, tono y parámetros PBR no son una especificación contractual.","note":"La apariencia gráfica no modifica ni confirma la especificación física del material."} | {"elementId":"found_0904_2f15f952c44af0","ifcGuid":"1Xg$LVvQbR6A6K6989IuIS","ifcClass":"IfcFooting","buildingId":"process_plant","buildingName":"Zona de separación de aire","sourceDocumentId":"LHD2609-JG00100-20260904","sourceRepresentationKind":"foundation"} | {"layerId":"foundations","layerName":"Cimentaciones","role":"Cimentación industrial","basis":"Clasificación por función del elemento; no modifica las especificaciones documentales."} | {"profileId":"concrete_ha30","name":"Hormigón HA-30","status":"criterio_visual","basis":"Interpretación visual del material documental; el acabado, tono y parámetros PBR no son una especificación contractual.","physicalMaterialUnchanged":true} | 0.4 | Hormigón HA-30 | Hormigón HA-30 | found_0904_2f15f952c44af0 | Nota general de pedestales 2CED5 | documentado | concrete_ha30 | [0.658824,0.658824,0.623529] | 0.94 | Zona de separación de aire; BIM · Cimentaciones | 1.12688 | 1.12688 | 0.4 | 285.1 | 285.5 | SUP-C40 | [] | ["C40"] | ZD1 / DZ-1 | ["2CD11","2CD5D","2CD29","2CDA5","2CD1A","2CD1B","2CD80","2CECA","2CEA5"] | SUP-C40/Cimentación de soporte de tuberías C40 · cuerpo de hormigón | foundation | Geometría de fabricante; implantación absoluta provisional |  | Cimentaciones de equipos y pedestales del fabricante · revisión recibida 04/09/2026 | 2CD11, 2CD5D, 2CD29, 2CDA5, 2CD1A, 2CD1B, 2CD80, 2CECA, 2CEA5 | -1 | -0.6 | 1 | Cotas relativas del dibujo. La equivalencia con un datum absoluto está pendiente. | Z del modelo = cota relativa + 1,10 m. Correspondencia provisional con 286,10 m; no es cota de obra confirmada. | Sección y contornos del fabricante; incidencias conservadas | 1 | 1 | Identificador original HA-40 en columna de posición; C40 se infiere por secuencia. Se conserva el original y no se interpreta como material. | Material: Hormigón HA-30
Cimentación de soporte de tuberías C40 · pedestal de hormigón | Parcela industrial Jinhong | Cimentación industrial | Cimentaciones de equipos y pedestales del fabricante · revisión recibida 04/09/2026 | 0.507099 | 0.507098 | 0.8 | 1.845 | 0.162 | process_plant | Zona de separación de aire | {"name":"Hormigón HA-30","status":"documentado","source":"Nota general de pedestales 2CED5"} | {"documented":[{"label":"Extensión local X","value":0.45,"unit":"m","source":"2CD11, 2CD5D, 2CD29, 2CDA5, 2CD1A, 2CD1B, 2CD80, 2CECA, 2CEA5","status":"derivada del contorno CAD"},{"label":"Extensión local Y","value":0.45,"unit":"m","source":"2CD11, 2CD5D, 2CD29, 2CDA5, 2CD1A, 2CD1B, 2CD80, 2CECA, 2CEA5","status":"derivada del contorno CAD"},{"label":"Cota inferior relativa adoptada","value":-0.6,"unit":"m","source":"ZD1 / DZ-1","status":"interpretación con conflicto conservado"},{"label":"Cota superior relativa adoptada","value":0.2,"unit":"m","source":"ZD1 / DZ-1","status":"documentada / separación por material"}],"geometry":[{"label":"Extensión de la malla en X","value":0.5070990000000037,"unit":"m","source":"Geometría releída del IFC; datum absoluto de proceso provisional","status":"derivado"},{"label":"Extensión de la malla en Y","value":0.5070979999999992,"unit":"m","source":"Geometría releída del IFC; datum absoluto de proceso provisional","status":"derivado"},{"label":"Extensión de la malla en Z","value":0.8,"unit":"m","source":"Geometría releída del IFC; datum absoluto de proceso provisional","status":"derivado"},{"label":"Cota inferior de visualización","value":285.5,"unit":"m","source":"Geometría releída del IFC; datum absoluto de proceso provisional","status":"derivado"},{"label":"Cota superior de visualización","value":286.3,"unit":"m","source":"Geometría releída del IFC; datum absoluto de proceso provisional","status":"derivado"}]} | {"documentId":"LHD2609-JG00100-20260904","title":"Cimentaciones de equipos y pedestales del fabricante · revisión recibida 04/09/2026","date":"2026-09-04","sheet":"ZD1 / DZ-1","fileName":"LHD2609-JG00100_20260904.dwg","revisionCaveat":"Fecha de revisión tomada del nombre recibido; cajetines internos mantienen 02/07/2026 y algunos textos de plantilla.","sourceFileSha256":"b42eb027b7bc0b14c38d1d13514f4899b58a732aa8d0ba2ccf10fa2fc3192890"} | provisional | ["Identificador original HA-40 en columna de posición; C40 se infiere por secuencia. Se conserva el original y no se interpreta como material."] | {"Cota inferior relativa (m)":-0.6,"Cota superior relativa (m)":0.2,"Cero absoluto de visualización (m)":286.1,"Estado del cero absoluto":"Provisional","Criterio":"Las cotas relativas proceden del dibujo; la equivalencia absoluta no está confirmada."} | {"boundingBoxM":{"min":[58.594426,37.851942,0.5],"max":[59.101525,38.35904,1.3]},"extentsM":[0.507099,0.507098,0.8],"meshSurfaceM2":1.845001,"meshVolumeM3":0.162,"closedSolid":true,"basis":"Magnitudes de las mallas representadas, no cantidades certificadas de obra, compra o fabricación. Las partes pueden compartir superficies; no se suman como un despiece de materiales."} | {"profileId":"concrete_ha30","name":"Hormigón HA-30","materialName":"Hormigón HA-30","physicalMaterialStatus":"documentado","physicalMaterialSource":"Nota general de pedestales 2CED5","appearanceStatus":"criterio_visual","appearanceBasis":"Interpretación visual del material documental; el acabado, tono y parámetros PBR no son una especificación contractual.","note":"La apariencia gráfica no modifica ni confirma la especificación física del material."} | {"elementId":"found_0904_16a00d538960ee","ifcGuid":"1vB4KQ_trGahYEHOnXX0DC","ifcClass":"IfcFooting","buildingId":"process_plant","buildingName":"Zona de separación de aire","sourceDocumentId":"LHD2609-JG00100-20260904","sourceRepresentationKind":"foundation"} | {"layerId":"foundations","layerName":"Cimentaciones","role":"Cimentación industrial","basis":"Clasificación por función del elemento; no modifica las especificaciones documentales."} | {"profileId":"concrete_ha30","name":"Hormigón HA-30","status":"criterio_visual","basis":"Interpretación visual del material documental; el acabado, tono y parámetros PBR no son una especificación contractual.","physicalMaterialUnchanged":true} | 0.162 | Hormigón HA-30 | Hormigón HA-30 | found_0904_16a00d538960ee | Nota general de pedestales 2CED5 | documentado | concrete_ha30 | [0.658824,0.658824,0.623529] | 0.94 | Zona de separación de aire; BIM · Cimentaciones | 0.507099 | 0.507098 | 0.8 | 285.5 | 286.3 | SUP-C40 | [] | ["C40"] | ZD1 / DZ-1 | ["2CD11","2CD5D","2CD29","2CDA5","2CD1A","2CD1B","2CD80","2CECA","2CEA5"] | SUP-C40/Cimentación de soporte de tuberías C40 · pedestal de hormigón | foundation | Geometría de fabricante; implantación absoluta provisional |  | Cimentaciones de equipos y pedestales del fabricante · revisión recibida 04/09/2026 | 2CD11, 2CD5D, 2CD29, 2CDA5, 2CD1A, 2CD1B, 2CD80, 2CECA, 2CEA5 | -0.6 | 0.2 | 0.2025 | Cotas relativas del dibujo. La equivalencia con un datum absoluto está pendiente. | Z del modelo = cota relativa + 1,10 m. Correspondencia provisional con 286,10 m; no es cota de obra confirmada. | Sección y contornos del fabricante; incidencias conservadas | 0.45 | 0.45 | Identificador original HA-40 en columna de posición; C40 se infiere por secuencia. Se conserva el original y no se interpreta como material. | Material: Hormigón HA-30
Cimentación de soporte de tuberías C41 · cuerpo de hormigón | Parcela industrial Jinhong | Cimentación industrial | Cimentaciones de equipos y pedestales del fabricante · revisión recibida 04/09/2026 | 1.12689 | 1.12688 | 0.4 | 3.6 | 0.4 | process_plant | Zona de separación de aire | {"name":"Hormigón HA-30","status":"documentado","source":"Nota general de pedestales 2CED5"} | {"documented":[{"label":"Extensión local X","value":1.0,"unit":"m","source":"2CD2C, 2CD5E, 2CD2F, 2CDA6, 2CD2D, 2CD2E, 2CD81, 2CECB, 2CEA6","status":"derivada del contorno CAD"},{"label":"Extensión local Y","value":1.0,"unit":"m","source":"2CD2C, 2CD5E, 2CD2F, 2CDA6, 2CD2D, 2CD2E, 2CD81, 2CECB, 2CEA6","status":"derivada del contorno CAD"},{"label":"Cota inferior relativa adoptada","value":-1.0,"unit":"m","source":"ZD1 / DZ-1","status":"documentada"},{"label":"Cota superior relativa adoptada","value":-0.6,"unit":"m","source":"ZD1 / DZ-1","status":"documentada / separación por material"}],"geometry":[{"label":"Extensión de la malla en X","value":1.1268850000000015,"unit":"m","source":"Geometría releída del IFC; datum absoluto de proceso provisional","status":"derivado"},{"label":"Extensión de la malla en Y","value":1.1268849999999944,"unit":"m","source":"Geometría releída del IFC; datum absoluto de proceso provisional","status":"derivado"},{"label":"Extensión de la malla en Z","value":0.4,"unit":"m","source":"Geometría releída del IFC; datum absoluto de proceso provisional","status":"derivado"},{"label":"Cota inferior de visualización","value":285.1,"unit":"m","source":"Geometría releída del IFC; datum absoluto de proceso provisional","status":"derivado"},{"label":"Cota superior de visualización","value":285.5,"unit":"m","source":"Geometría releída del IFC; datum absoluto de proceso provisional","status":"derivado"}]} | {"documentId":"LHD2609-JG00100-20260904","title":"Cimentaciones de equipos y pedestales del fabricante · revisión recibida 04/09/2026","date":"2026-09-04","sheet":"ZD1 / DZ-1","fileName":"LHD2609-JG00100_20260904.dwg","revisionCaveat":"Fecha de revisión tomada del nombre recibido; cajetines internos mantienen 02/07/2026 y algunos textos de plantilla.","sourceFileSha256":"b42eb027b7bc0b14c38d1d13514f4899b58a732aa8d0ba2ccf10fa2fc3192890"} | provisional | [] | {"Cota inferior relativa (m)":-1.0,"Cota superior relativa (m)":-0.6,"Cero absoluto de visualización (m)":286.1,"Estado del cero absoluto":"Provisional","Criterio":"Las cotas relativas proceden del dibujo; la equivalencia absoluta no está confirmada."} | {"boundingBoxM":{"min":[59.869622,37.324122,0.1],"max":[60.996507,38.451007,0.5]},"extentsM":[1.126885,1.126885,0.4],"meshSurfaceM2":3.600001,"meshVolumeM3":0.4,"closedSolid":true,"basis":"Magnitudes de las mallas representadas, no cantidades certificadas de obra, compra o fabricación. Las partes pueden compartir superficies; no se suman como un despiece de materiales."} | {"profileId":"concrete_ha30","name":"Hormigón HA-30","materialName":"Hormigón HA-30","physicalMaterialStatus":"documentado","physicalMaterialSource":"Nota general de pedestales 2CED5","appearanceStatus":"criterio_visual","appearanceBasis":"Interpretación visual del material documental; el acabado, tono y parámetros PBR no son una especificación contractual.","note":"La apariencia gráfica no modifica ni confirma la especificación física del material."} | {"elementId":"found_0904_ddf20c3aded2d9","ifcGuid":"33iHO1q7TRWRf5VneDdbYN","ifcClass":"IfcFooting","buildingId":"process_plant","buildingName":"Zona de separación de aire","sourceDocumentId":"LHD2609-JG00100-20260904","sourceRepresentationKind":"foundation"} | {"layerId":"foundations","layerName":"Cimentaciones","role":"Cimentación industrial","basis":"Clasificación por función del elemento; no modifica las especificaciones documentales."} | {"profileId":"concrete_ha30","name":"Hormigón HA-30","status":"criterio_visual","basis":"Interpretación visual del material documental; el acabado, tono y parámetros PBR no son una especificación contractual.","physicalMaterialUnchanged":true} | 0.4 | Hormigón HA-30 | Hormigón HA-30 | found_0904_ddf20c3aded2d9 | Nota general de pedestales 2CED5 | documentado | concrete_ha30 | [0.658824,0.658824,0.623529] | 0.94 | Zona de separación de aire; BIM · Cimentaciones | 1.12689 | 1.12688 | 0.4 | 285.1 | 285.5 | SUP-C41 | [] | ["C41"] | ZD1 / DZ-1 | ["2CD2C","2CD5E","2CD2F","2CDA6","2CD2D","2CD2E","2CD81","2CECB","2CEA6"] | SUP-C41/Cimentación de soporte de tuberías C41 · cuerpo de hormigón | foundation | Geometría de fabricante; implantación absoluta provisional |  | Cimentaciones de equipos y pedestales del fabricante · revisión recibida 04/09/2026 | 2CD2C, 2CD5E, 2CD2F, 2CDA6, 2CD2D, 2CD2E, 2CD81, 2CECB, 2CEA6 | -1 | -0.6 | 1 | Cotas relativas del dibujo. La equivalencia con un datum absoluto está pendiente. | Z del modelo = cota relativa + 1,10 m. Correspondencia provisional con 286,10 m; no es cota de obra confirmada. | Contornos y sección documentados por el fabricante | 1 | 1 | Material: Hormigón HA-30
Cimentación de soporte de tuberías C41 · pedestal de hormigón | Parcela industrial Jinhong | Cimentación industrial | Cimentaciones de equipos y pedestales del fabricante · revisión recibida 04/09/2026 | 0.507098 | 0.507098 | 0.8 | 1.845 | 0.162 | process_plant | Zona de separación de aire | {"name":"Hormigón HA-30","status":"documentado","source":"Nota general de pedestales 2CED5"} | {"documented":[{"label":"Extensión local X","value":0.45,"unit":"m","source":"2CD2C, 2CD5E, 2CD2F, 2CDA6, 2CD2D, 2CD2E, 2CD81, 2CECB, 2CEA6","status":"derivada del contorno CAD"},{"label":"Extensión local Y","value":0.45,"unit":"m","source":"2CD2C, 2CD5E, 2CD2F, 2CDA6, 2CD2D, 2CD2E, 2CD81, 2CECB, 2CEA6","status":"derivada del contorno CAD"},{"label":"Cota inferior relativa adoptada","value":-0.6,"unit":"m","source":"ZD1 / DZ-1","status":"documentada"},{"label":"Cota superior relativa adoptada","value":0.2,"unit":"m","source":"ZD1 / DZ-1","status":"documentada / separación por material"}],"geometry":[{"label":"Extensión de la malla en X","value":0.5070979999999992,"unit":"m","source":"Geometría releída del IFC; datum absoluto de proceso provisional","status":"derivado"},{"label":"Extensión de la malla en Y","value":0.5070979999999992,"unit":"m","source":"Geometría releída del IFC; datum absoluto de proceso provisional","status":"derivado"},{"label":"Extensión de la malla en Z","value":0.8,"unit":"m","source":"Geometría releída del IFC; datum absoluto de proceso provisional","status":"derivado"},{"label":"Cota inferior de visualización","value":285.5,"unit":"m","source":"Geometría releída del IFC; datum absoluto de proceso provisional","status":"derivado"},{"label":"Cota superior de visualización","value":286.3,"unit":"m","source":"Geometría releída del IFC; datum absoluto de proceso provisional","status":"derivado"}]} | {"documentId":"LHD2609-JG00100-20260904","title":"Cimentaciones de equipos y pedestales del fabricante · revisión recibida 04/09/2026","date":"2026-09-04","sheet":"ZD1 / DZ-1","fileName":"LHD2609-JG00100_20260904.dwg","revisionCaveat":"Fecha de revisión tomada del nombre recibido; cajetines internos mantienen 02/07/2026 y algunos textos de plantilla.","sourceFileSha256":"b42eb027b7bc0b14c38d1d13514f4899b58a732aa8d0ba2ccf10fa2fc3192890"} | provisional | [] | {"Cota inferior relativa (m)":-0.6,"Cota superior relativa (m)":0.2,"Cero absoluto de visualización (m)":286.1,"Estado del cero absoluto":"Provisional","Criterio":"Las cotas relativas proceden del dibujo; la equivalencia absoluta no está confirmada."} | {"boundingBoxM":{"min":[60.179516,37.634016,0.5],"max":[60.686614,38.141114,1.3]},"extentsM":[0.507098,0.507098,0.8],"meshSurfaceM2":1.845,"meshVolumeM3":0.162,"closedSolid":true,"basis":"Magnitudes de las mallas representadas, no cantidades certificadas de obra, compra o fabricación. Las partes pueden compartir superficies; no se suman como un despiece de materiales."} | {"profileId":"concrete_ha30","name":"Hormigón HA-30","materialName":"Hormigón HA-30","physicalMaterialStatus":"documentado","physicalMaterialSource":"Nota general de pedestales 2CED5","appearanceStatus":"criterio_visual","appearanceBasis":"Interpretación visual del material documental; el acabado, tono y parámetros PBR no son una especificación contractual.","note":"La apariencia gráfica no modifica ni confirma la especificación física del material."} | {"elementId":"found_0904_9d7eac2d94e1b5","ifcGuid":"2RNPxuwCjGhQIXVayEu6yJ","ifcClass":"IfcFooting","buildingId":"process_plant","buildingName":"Zona de separación de aire","sourceDocumentId":"LHD2609-JG00100-20260904","sourceRepresentationKind":"foundation"} | {"layerId":"foundations","layerName":"Cimentaciones","role":"Cimentación industrial","basis":"Clasificación por función del elemento; no modifica las especificaciones documentales."} | {"profileId":"concrete_ha30","name":"Hormigón HA-30","status":"criterio_visual","basis":"Interpretación visual del material documental; el acabado, tono y parámetros PBR no son una especificación contractual.","physicalMaterialUnchanged":true} | 0.162 | Hormigón HA-30 | Hormigón HA-30 | found_0904_9d7eac2d94e1b5 | Nota general de pedestales 2CED5 | documentado | concrete_ha30 | [0.658824,0.658824,0.623529] | 0.94 | Zona de separación de aire; BIM · Cimentaciones | 0.507098 | 0.507098 | 0.8 | 285.5 | 286.3 | SUP-C41 | [] | ["C41"] | ZD1 / DZ-1 | ["2CD2C","2CD5E","2CD2F","2CDA6","2CD2D","2CD2E","2CD81","2CECB","2CEA6"] | SUP-C41/Cimentación de soporte de tuberías C41 · pedestal de hormigón | foundation | Geometría de fabricante; implantación absoluta provisional |  | Cimentaciones de equipos y pedestales del fabricante · revisión recibida 04/09/2026 | 2CD2C, 2CD5E, 2CD2F, 2CDA6, 2CD2D, 2CD2E, 2CD81, 2CECB, 2CEA6 | -0.6 | 0.2 | 0.2025 | Cotas relativas del dibujo. La equivalencia con un datum absoluto está pendiente. | Z del modelo = cota relativa + 1,10 m. Correspondencia provisional con 286,10 m; no es cota de obra confirmada. | Contornos y sección documentados por el fabricante | 0.45 | 0.45 | Material: Hormigón HA-30

# IfcGeographicElement, Terreno existente reconstruido a partir de puntos topográficos · oculto por defecto
In: Parcela industrial Jinhong
Description: Terreno existente de referencia; PredefinedType: TERRAIN; Document: Puntos topográficos XYZ de referencia · extracción interna derivada, no oficial; Group: Terreno existente; BIM · Terreno existente
JH_DimensionesDelModelo - Extensión de la malla en X: 140.705 m; Extensión de la malla en Y: 104.889 m; Extensión de la malla en Z: 3.067 m; Cota inferior del modelo: 285.007 m; Cota superior del modelo: 288.074 m; Triángulos de la superficie recortada: 258
JH_MagnitudesGeometricas - ExtensionX: 140.705 m; ExtensionY: 104.889 m; ExtensionZ: 3.067 m; SuperficieDeLaMalla: 9169.74 m2
JH_InformacionBIM - buildingId: site; buildingName: Urbanización y parcela; level: Terreno existente · datum vertical sin confirmar; category: Terreno existente de referencia; ifcClass: IfcGeographicElement; material: {"name":"No especificado","source":"Sin especificación de material en la documentación revisada","status":"unknown"}; dimensions: {"documented":[{"label":"Puntos XYZ de origen","value":624,"unit":"puntos","source":"TOPO-20260809","status":"derivado"}],"geometry":[{"label":"Extensión de la malla en X","value":140.705,"unit":"m","source":"Calculada a partir de los vértices del modelo","status":"derivado"},{"label":"Extensión de la malla en Y","value":104.889,"unit":"m","source":"Calculada a partir de los vértices del modelo","status":"derivado"},{"label":"Extensión de la malla en Z","value":3.067,"unit":"m","source":"Calculada a partir de los vértices del modelo","status":"derivado"},{"label":"Cota inferior del modelo","value":285.007,"unit":"m","source":"Coordenada Z mínima de la malla más origen vertical de 285 m","status":"derivado"},{"label":"Cota superior del modelo","value":288.074,"unit":"m","source":"Coordenada Z máxima de la malla más origen vertical de 285 m","status":"derivado"},{"label":"Triángulos de la superficie recortada","value":258,"unit":"triángulos","source":"Malla de Delaunay derivada","status":"derivado"}],"notes":["Las extensiones de la malla se miden en los ejes del proyecto tras el giro de implantación; no sustituyen las dimensiones locales del fabricante.","La envolvente, su volumen y los espesores de visualización no son volúmenes de material ni cantidades de compra, construcción o fabricación.","Las dimensiones documentadas distinguen cotas explícitas y medidas extraídas de contornos CAD; las dimensiones geométricas describen únicamente la malla publicada."]}; source: {"documentId":"TOPO-20260809","title":"Puntos topográficos XYZ de referencia · extracción interna derivada, no oficial","sheet":"CSV de 624 puntos; sin lámina","date":"2026-08-09"}; status: derivado; positioning: {"horizontalStatus":"derivado","verticalStatus":"provisional","baseElevationM":285.007,"note":"Se conservan las Z del DWG topográfico de origen; datum vertical pendiente de confirmar."}; issues: ["Nueva triangulación de Delaunay de 624 puntos de origen, recortada al interior de la parcela. No es el TIN original del DWG topográfico.","Se conservan las Z del DWG topográfico de origen; datum vertical pendiente de confirmar.","CSV interno derivado y trazable; no constituye un nuevo levantamiento topográfico emitido."]; geometryMetrics: {"boundingBoxM":{"min":[-5.784,4.083,0.007],"max":[134.921,108.972,3.074]},"extentsM":[140.705,104.889,3.067],"meshSurfaceM2":9169.738498,"meshVolumeM3":null,"closedSolid":false,"basis":"Geometría triangulada releída del IFC; envolventes y magnitudes no contractuales."}; ifcAssociations: {"material":false,"document":true,"quantities":true,"containerGuid":"17utmjd_LKsAVvPyuSUhFt","containerName":"Parcela industrial Jinhong"}; visualLayer: {"id":"terrain","name":"Terreno existente"}; materialAppearance: {"profileId":"terrain","name":"Terreno existente · tierra natural","materialName":"No especificado","physicalMaterialStatus":"unknown","physicalMaterialSource":"Sin especificación de material en la documentación revisada","appearanceStatus":"provisional","appearanceBasis":"Apariencia terrosa ilustrativa de la superficie topográfica reconstruida.","note":"La apariencia gráfica no modifica ni confirma la especificación física del material."}; componentSeparation: {"status":"objeto_independiente","note":"Control de visibilidad del objeto completo; la clasificación no altera la malla."}; visualizationIdentity: {"elementId":"site_008","ifcGuid":"2luYgi7KrLAg4dakSudMII","ifcClass":"IfcGeographicElement","buildingId":"site","buildingName":"Urbanización y parcela","sourceDocumentId":"TOPO-20260809","sourceRepresentationKind":"documentary_mesh"}; classification: {"layerId":"terrain","layerName":"Terreno existente","role":"Terreno existente de referencia","basis":"Clasificación por función del elemento; no modifica las especificaciones documentales."}; layerId: terrain; appearance: {"profileId":"terrain","name":"Terreno existente · tierra natural","status":"provisional","basis":"Apariencia terrosa ilustrativa de la superficie topográfica reconstruida.","physicalMaterialUnchanged":true}
JH_Trazabilidad - Documento de origen: Puntos topográficos XYZ de referencia · extracción interna derivada, no oficial · 2026-08-09 · CSV de 624 puntos; sin lámina; Número de puntos de origen: 624; Número de triángulos utilizados: 258; Sistema de referencia horizontal: ETRS89 / UTM 29N (EPSG:25829); Referencia altimétrica: Se conservan las Z del DWG topográfico de origen; datum vertical pendiente de confirmar.; Estado de la geometría: Nueva triangulación de Delaunay de 624 puntos de origen, recortada al interior de la parcela. No es el TIN original del DWG topográfico.; Configuración de visualización: Oculto por defecto; visualizar de forma separada respecto a la superficie de proyecto.; Estado de los datos de origen: CSV interno derivado y trazable; no constituye un nuevo levantamiento topográfico emitido.; Identificador del objeto: site_008; Disciplina: Terreno existente; Clase IFC: IfcGeographicElement; Fase del modelo: V0.1 · Reconstrucción a partir de planos y coordinación preliminar; Representación geométrica IFC: Superficie de referencia del terreno en IFC4; Aplicabilidad a mediciones: Los equipos se representan mediante envolventes. Los espesores y alturas supuestos y el volumen de las envolventes no representan cantidades de materiales, compras, construcción o fabricación.; Material: No especificado; Estado de la información: derivado; Capa BIM: Terreno existente; Acabado de visualización: Terreno existente · tierra natural; Estado del acabado: provisional; Identificador: site_008; Categoria: Terreno existente de referencia; ClaseIFC: IfcGeographicElement; EstadoDeInformacion: derivado; DocumentoFuente: {"documentId":"TOPO-20260809","title":"Puntos topográficos XYZ de referencia · extracción interna derivada, no oficial","sheet":"CSV de 624 puntos; sin lámina","date":"2026-08-09"}; IncidenciasPendientes: ["Nueva triangulación de Delaunay de 624 puntos de origen, recortada al interior de la parcela. No es el TIN original del DWG topográfico.","Se conservan las Z del DWG topográfico de origen; datum vertical pendiente de confirmar.","CSV interno derivado y trazable; no constituye un nuevo levantamiento topográfico emitido."]; UsoDeLasMagnitudes: Geometría de coordinación. Los volúmenes de referencia y subcomponentes no son cantidades de material ni componentes de fabricación certificados.
JH_CriterioDePosicion - PosicionYEstado: {"horizontalStatus":"derivado","verticalStatus":"provisional","baseElevationM":285.007,"note":"Se conservan las Z del DWG topográfico de origen; datum vertical pendiente de confirmar."}
JH_EvidenciaDeMaterial - name: No especificado; source: Sin especificación de material en la documentación revisada; status: unknown
JH_DimensionesDocumentadas - Puntos XYZ de origen: 624
JH_CapaBIM - IdentificadorCapa: terrain; NombreCapa: Terreno existente; Funcion: Terreno existente de referencia; VisibilidadInicial: no
JH_AcabadoVisual - Perfil: terrain; Acabado: Terreno existente · tierra natural; ColorRGB: [0.607843,0.545098,0.447059]; Rugosidad: 1; Metallicidad: 0; Estado: provisional; Referencia: Apariencia terrosa ilustrativa de la superficie topográfica reconstruida.; Nota: La apariencia no certifica el material físico ni el acabado de fabricación.

# IfcGeographicElement: Aceras y bordes viarios · simplificados
In: Parcela industrial Jinhong
Description: Entorno de coordinación: trazados derivados de las fuentes indicadas por elemento; cotas, espesores, acabados y mobiliario orientativos cuando no están documentados. No acredita propiedad, servidumbres ni cantidades de obra y no es una base de construcción.; PredefinedType: USERDEFINED; Document: Entorno de Expacio Mérida · Catastro INSPIRE, PNOA y levantamiento Berrio; Levantamiento Berrio · parcelas I-27 Vial 3 e I-18 Vial 4; IGN · ortofotografía PNOA de máxima actualidad; Indicación del cliente · entorno de 200 m con aparcamientos y luminarias ilustrativos; Group: BIM · Entorno · viales y aceras
JH_InformacionBIM - buildingId: context; buildingName: Entorno exterior de la parcela; level: Exterior · contexto de 200 m; category: Aceras y bordes viarios · simplificados; ifcClass: IfcGeographicElement; status: derivado; source: {"documentId":"JH-CONTEXT-GIS-20260909","title":"Entorno de Expacio Mérida · Catastro INSPIRE, PNOA y levantamiento Berrio","date":"2026-09-09","url":"https://www.catastro.hacienda.gob.es/webinspire/index.html","note":"Consulta cartográfica 09/09/2026. Linderos catastrales consultados en el servicio vigente; viales contrastados con PNOA y bordes levantados del paquete topográfico recibido el 28/07/2026. La fecha de consulta no es la fecha de vuelo. Se conserva el lindero del proyecto del 31/07/2026."}; material: {"name":"Acera exterior","status":"provisional","source":"Acabado visual aproximado; no especificación de proyecto."}; appearance: {"profileId":"ctx_walk","name":"Acera exterior","status":"criterio_visual","basis":"Acabado de contexto orientativo, sin especificación de obra."}; dimensions: {"documented":[],"assumed":[{"label":"Cota exterior","value":"Plano simplificado ajustado a puntos de acera; extrapolación orientativa","unit":""}],"geometry":[{"label":"Extensión representada X","value":529.6009,"unit":"m"},{"label":"Extensión representada Y","value":485.3274,"unit":"m"},{"label":"Extensión representada Z","value":6.0801,"unit":"m"}]}; classification: {"layerId":"context_roads","layerName":"Entorno · viales y aceras","function":"Aceras y bordes viarios · simplificados"}; visualLayer: {"id":"context_roads","name":"Entorno · viales y aceras","defaultVisible":false}; representationKind: contexto_cartografico_derivado; quantityEligible: no; positioning: {"Sistema":"ETRS89 / UTM 29N · metros","Origen del modelo":"X 729400 · Y 4301550 · Z 285 m","Alcance":"Hasta 200 m desde el lindero del proyecto; solo exterior de parcela","Planta":"Catastro vigente consultado, contraste con ortofoto PNOA y levantamiento de aceras","Altimetría":"Plano ajustado a 213 puntos XYZ de aceras, extrapolado al resto del contexto; no es un MDT levantado"}; issues: ["Contexto para lectura del emplazamiento; planta derivada de cartografía, cotas y detalles simplificados. No para construcción ni mediciones de obra.","Las mediciones en el entorno expresan la geometría representada y conservan la precisión de su fuente."]; geometryMetrics: {"boundingBoxM":{"min":[-205.956689,-197.148812,-1.909383],"max":[323.644195,288.178594,4.170706]},"extentsM":[529.600884,485.327406,6.080089],"meshSurfaceM2":12541.799246,"meshVolumeM3":1047.873178,"closedSolid":true,"basis":"Entorno de coordinación: trazados derivados de las fuentes indicadas por elemento; cotas, espesores, acabados y mobiliario orientativos cuando no están documentados. No acredita propiedad, servidumbres ni cantidades de obra y no es una base de construcción."}
JH_Trazabilidad - Origen: Entorno de Expacio Mérida · Catastro INSPIRE, PNOA y levantamiento Berrio; Estado: derivado; Capa BIM: Entorno · viales y aceras; Mediciones de obra: Excluido; Identificador: CTX-SIDEWALKS; Categoria: Aceras y bordes viarios · simplificados; ClaseIFC: IfcGeographicElement; EstadoDeInformacion: derivado; DocumentoFuente: {"documentId":"JH-CONTEXT-GIS-20260909","title":"Entorno de Expacio Mérida · Catastro INSPIRE, PNOA y levantamiento Berrio","date":"2026-09-09","url":"https://www.catastro.hacienda.gob.es/webinspire/index.html","note":"Consulta cartográfica 09/09/2026. Linderos catastrales consultados en el servicio vigente; viales contrastados con PNOA y bordes levantados del paquete topográfico recibido el 28/07/2026. La fecha de consulta no es la fecha de vuelo. Se conserva el lindero del proyecto del 31/07/2026."}; IncidenciasPendientes: ["Contexto para lectura del emplazamiento; planta derivada de cartografía, cotas y detalles simplificados. No para construcción ni mediciones de obra.","Las mediciones en el entorno expresan la geometría representada y conservan la precisión de su fuente."]; UsoDeLasMagnitudes: Entorno de coordinación: trazados derivados de las fuentes indicadas por elemento; cotas, espesores, acabados y mobiliario orientativos cuando no están documentados. No acredita propiedad, servidumbres ni cantidades de obra y no es una base de construcción.
JH_CriterioDePosicion - PosicionYEstado: {"Sistema":"ETRS89 / UTM 29N · metros","Origen del modelo":"X 729400 · Y 4301550 · Z 285 m","Alcance":"Hasta 200 m desde el lindero del proyecto; solo exterior de parcela","Planta":"Catastro vigente consultado, contraste con ortofoto PNOA y levantamiento de aceras","Altimetría":"Plano ajustado a 213 puntos XYZ de aceras, extrapolado al resto del contexto; no es un MDT levantado"}
JH_EvidenciaDeMaterial - name: Acera exterior; status: provisional; source: Acabado visual aproximado; no especificación de proyecto.
JH_CapaBIM - IdentificadorCapa: context_roads; NombreCapa: Entorno · viales y aceras; Funcion: Aceras y bordes viarios · simplificados; VisibilidadInicial: no
JH_EntornoContexto - Estado: derivado; Origen: {"documentId":"JH-CONTEXT-GIS-20260909","title":"Entorno de Expacio Mérida · Catastro INSPIRE, PNOA y levantamiento Berrio","date":"2026-09-09","url":"https://www.catastro.hacienda.gob.es/webinspire/index.html","note":"Consulta cartográfica 09/09/2026. Linderos catastrales consultados en el servicio vigente; viales contrastados con PNOA y bordes levantados del paquete topográfico recibido el 28/07/2026. La fecha de consulta no es la fecha de vuelo. Se conserva el lindero del proyecto del 31/07/2026."}; Posicion: {"Sistema":"ETRS89 / UTM 29N · metros","Origen del modelo":"X 729400 · Y 4301550 · Z 285 m","Alcance":"Hasta 200 m desde el lindero del proyecto; solo exterior de parcela","Planta":"Catastro vigente consultado, contraste con ortofoto PNOA y levantamiento de aceras","Altimetría":"Plano ajustado a 213 puntos XYZ de aceras, extrapolado al resto del contexto; no es un MDT levantado"}; DimensionesSupuestas: [{"label":"Cota exterior","value":"Plano simplificado ajustado a puntos de acera; extrapolación orientativa","unit":""}]; IncluirEnMediciones: no; EsquemaIlustrativo: no; Criterio: Entorno de coordinación: trazados derivados de las fuentes indicadas por elemento; cotas, espesores, acabados y mobiliario orientativos cuando no están documentados. No acredita propiedad, servidumbres ni cantidades de obra y no es una base de construcción.

# IfcGeographicElement: Glorieta e isletas divisorias · aproximadas
In: Parcela industrial Jinhong
Description: Entorno de coordinación: trazados derivados de las fuentes indicadas por elemento; cotas, espesores, acabados y mobiliario orientativos cuando no están documentados. No acredita propiedad, servidumbres ni cantidades de obra y no es una base de construcción.; PredefinedType: USERDEFINED; Document: Entorno de Expacio Mérida · Catastro INSPIRE, PNOA y levantamiento Berrio; Levantamiento Berrio · parcelas I-27 Vial 3 e I-18 Vial 4; IGN · ortofotografía PNOA de máxima actualidad; Indicación del cliente · entorno de 200 m con aparcamientos y luminarias ilustrativos; Group: BIM · Entorno · viales y aceras
JH_InformacionBIM - buildingId: context; buildingName: Entorno exterior de la parcela; level: Exterior · contexto de 200 m; category: Glorieta e isletas divisorias · aproximadas; ifcClass: IfcGeographicElement; status: derivado; source: {"documentId":"JH-CONTEXT-GIS-20260909","title":"Entorno de Expacio Mérida · Catastro INSPIRE, PNOA y levantamiento Berrio","date":"2026-09-09","url":"https://www.catastro.hacienda.gob.es/webinspire/index.html","note":"Consulta cartográfica 09/09/2026. Linderos catastrales consultados en el servicio vigente; viales contrastados con PNOA y bordes levantados del paquete topográfico recibido el 28/07/2026. La fecha de consulta no es la fecha de vuelo. Se conserva el lindero del proyecto del 31/07/2026."}; material: {"name":"Isletas y medianas","status":"provisional","source":"Acabado visual aproximado; no especificación de proyecto."}; appearance: {"profileId":"ctx_median","name":"Isletas y medianas","status":"criterio_visual","basis":"Acabado de contexto orientativo, sin especificación de obra."}; dimensions: {"documented":[],"assumed":[{"label":"Radio de la isla de glorieta interpretado en imagen","value":24.2,"unit":"m"},{"label":"Anchos de medianas interpretados","value":"1,3–2,6","unit":"m"}],"geometry":[]}; classification: {"layerId":"context_roads","layerName":"Entorno · viales y aceras","function":"Glorieta e isletas divisorias · aproximadas"}; visualLayer: {"id":"context_roads","name":"Entorno · viales y aceras","defaultVisible":false}; representationKind: contexto_cartografico_derivado; quantityEligible: no; positioning: {"Sistema":"ETRS89 / UTM 29N · metros","Origen del modelo":"X 729400 · Y 4301550 · Z 285 m","Alcance":"Hasta 200 m desde el lindero del proyecto; solo exterior de parcela","Planta":"Catastro vigente consultado, contraste con ortofoto PNOA y levantamiento de aceras","Altimetría":"Plano ajustado a 213 puntos XYZ de aceras, extrapolado al resto del contexto; no es un MDT levantado"}; issues: ["Contexto para lectura del emplazamiento; planta derivada de cartografía, cotas y detalles simplificados. No para construcción ni mediciones de obra.","Las mediciones en el entorno expresan la geometría representada y conservan la precisión de su fuente."]; geometryMetrics: {"boundingBoxM":{"min":[-206.095411,-93.647842,-1.930127],"max":[320.702515,272.387043,4.091547]},"extentsM":[526.797926,366.034885,6.021674],"meshSurfaceM2":6323.521409,"meshVolumeM3":658.086846,"closedSolid":true,"basis":"Entorno de coordinación: trazados derivados de las fuentes indicadas por elemento; cotas, espesores, acabados y mobiliario orientativos cuando no están documentados. No acredita propiedad, servidumbres ni cantidades de obra y no es una base de construcción."}
JH_Trazabilidad - Origen: Entorno de Expacio Mérida · Catastro INSPIRE, PNOA y levantamiento Berrio; Estado: derivado; Capa BIM: Entorno · viales y aceras; Mediciones de obra: Excluido; Identificador: CTX-ISLANDS; Categoria: Glorieta e isletas divisorias · aproximadas; ClaseIFC: IfcGeographicElement; EstadoDeInformacion: derivado; DocumentoFuente: {"documentId":"JH-CONTEXT-GIS-20260909","title":"Entorno de Expacio Mérida · Catastro INSPIRE, PNOA y levantamiento Berrio","date":"2026-09-09","url":"https://www.catastro.hacienda.gob.es/webinspire/index.html","note":"Consulta cartográfica 09/09/2026. Linderos catastrales consultados en el servicio vigente; viales contrastados con PNOA y bordes levantados del paquete topográfico recibido el 28/07/2026. La fecha de consulta no es la fecha de vuelo. Se conserva el lindero del proyecto del 31/07/2026."}; IncidenciasPendientes: ["Contexto para lectura del emplazamiento; planta derivada de cartografía, cotas y detalles simplificados. No para construcción ni mediciones de obra.","Las mediciones en el entorno expresan la geometría representada y conservan la precisión de su fuente."]; UsoDeLasMagnitudes: Entorno de coordinación: trazados derivados de las fuentes indicadas por elemento; cotas, espesores, acabados y mobiliario orientativos cuando no están documentados. No acredita propiedad, servidumbres ni cantidades de obra y no es una base de construcción.
JH_CriterioDePosicion - PosicionYEstado: {"Sistema":"ETRS89 / UTM 29N · metros","Origen del modelo":"X 729400 · Y 4301550 · Z 285 m","Alcance":"Hasta 200 m desde el lindero del proyecto; solo exterior de parcela","Planta":"Catastro vigente consultado, contraste con ortofoto PNOA y levantamiento de aceras","Altimetría":"Plano ajustado a 213 puntos XYZ de aceras, extrapolado al resto del contexto; no es un MDT levantado"}
JH_EvidenciaDeMaterial - name: Isletas y medianas; status: provisional; source: Acabado visual aproximado; no especificación de proyecto.
JH_CapaBIM - IdentificadorCapa: context_roads; NombreCapa: Entorno · viales y aceras; Funcion: Glorieta e isletas divisorias · aproximadas; VisibilidadInicial: no
JH_EntornoContexto - Estado: derivado; Origen: {"documentId":"JH-CONTEXT-GIS-20260909","title":"Entorno de Expacio Mérida · Catastro INSPIRE, PNOA y levantamiento Berrio","date":"2026-09-09","url":"https://www.catastro.hacienda.gob.es/webinspire/index.html","note":"Consulta cartográfica 09/09/2026. Linderos catastrales consultados en el servicio vigente; viales contrastados con PNOA y bordes levantados del paquete topográfico recibido el 28/07/2026. La fecha de consulta no es la fecha de vuelo. Se conserva el lindero del proyecto del 31/07/2026."}; Posicion: {"Sistema":"ETRS89 / UTM 29N · metros","Origen del modelo":"X 729400 · Y 4301550 · Z 285 m","Alcance":"Hasta 200 m desde el lindero del proyecto; solo exterior de parcela","Planta":"Catastro vigente consultado, contraste con ortofoto PNOA y levantamiento de aceras","Altimetría":"Plano ajustado a 213 puntos XYZ de aceras, extrapolado al resto del contexto; no es un MDT levantado"}; DimensionesSupuestas: [{"label":"Radio de la isla de glorieta interpretado en imagen","value":24.2,"unit":"m"},{"label":"Anchos de medianas interpretados","value":"1,3–2,6","unit":"m"}]; IncluirEnMediciones: no; EsquemaIlustrativo: no; Criterio: Entorno de coordinación: trazados derivados de las fuentes indicadas por elemento; cotas, espesores, acabados y mobiliario orientativos cuando no están documentados. No acredita propiedad, servidumbres ni cantidades de obra y no es una base de construcción.

# IfcGeographicElement: Parcela catastral próxima · 9116001QD2091N
In: Parcela industrial Jinhong
Description: Entorno de coordinación: trazados derivados de las fuentes indicadas por elemento; cotas, espesores, acabados y mobiliario orientativos cuando no están documentados. No acredita propiedad, servidumbres ni cantidades de obra y no es una base de construcción.; PredefinedType: USERDEFINED; Document: Dirección General del Catastro · parcela 9116001QD2091N; Entorno de Expacio Mérida · Catastro INSPIRE, PNOA y levantamiento Berrio; Levantamiento Berrio · parcelas I-27 Vial 3 e I-18 Vial 4; IGN · ortofotografía PNOA de máxima actualidad; Indicación del cliente · entorno de 200 m con aparcamientos y luminarias ilustrativos; Group: BIM · Entorno · parcelas catastrales
JH_InformacionBIM - buildingId: context; buildingName: Entorno exterior de la parcela; level: Exterior · contexto de 200 m; category: Parcela catastral próxima · 9116001QD2091N; ifcClass: IfcGeographicElement; status: derivado; source: {"documentId":"SDGC-CP-9116001QD2091N","title":"Dirección General del Catastro · parcela 9116001QD2091N","date":"2026-09-09","url":"https://www.catastro.hacienda.gob.es/webinspire/index.html","note":"Geometría del servicio vigente consultado el 09/09/2026. La fecha de alta del registro no es una fecha de levantamiento. Contexto recortado a 200 m; no identifica la nueva parcela I-18N."}; material: {"name":"Parcela exterior · suelo de referencia","status":"provisional","source":"Acabado visual aproximado; no especificación de proyecto."}; appearance: {"profileId":"ctx_plot_0","name":"Parcela exterior · suelo de referencia","status":"criterio_visual","basis":"Acabado de contexto orientativo, sin especificación de obra."}; dimensions: {"documented":[],"assumed":[{"label":"Cota exterior","value":"Plano simplificado ajustado a puntos de acera; extrapolación orientativa","unit":""}],"geometry":[{"label":"Extensión representada X","value":192.479,"unit":"m"},{"label":"Extensión representada Y","value":226.0102,"unit":"m"},{"label":"Extensión representada Z","value":2.7003,"unit":"m"}]}; classification: {"layerId":"context_parcels","layerName":"Entorno · parcelas catastrales","function":"Parcela catastral próxima · 9116001QD2091N"}; visualLayer: {"id":"context_parcels","name":"Entorno · parcelas catastrales","defaultVisible":false}; representationKind: contexto_cartografico_derivado; quantityEligible: no; positioning: {"Sistema":"ETRS89 / UTM 29N · metros","Origen del modelo":"X 729400 · Y 4301550 · Z 285 m","Alcance":"Hasta 200 m desde el lindero del proyecto; solo exterior de parcela","Planta":"Catastro vigente consultado, contraste con ortofoto PNOA y levantamiento de aceras","Altimetría":"Plano ajustado a 213 puntos XYZ de aceras, extrapolado al resto del contexto; no es un MDT levantado"}; issues: ["Contexto para lectura del emplazamiento; planta derivada de cartografía, cotas y detalles simplificados. No para construcción ni mediciones de obra.","Las mediciones en el entorno expresan la geometría representada y conservan la precisión de su fuente."]; cadastralReference: 9116001QD2091N; cadastralRecordBeginLifespan: 2018-01-15T00:00:00; geometryMetrics: {"boundingBoxM":{"min":[-205.56905,27.12045,-1.918951],"max":[-13.090083,253.130683,0.781388]},"extentsM":[192.478967,226.010233,2.700339],"meshSurfaceM2":70587.773679,"meshVolumeM3":2821.016124,"closedSolid":true,"basis":"Entorno de coordinación: trazados derivados de las fuentes indicadas por elemento; cotas, espesores, acabados y mobiliario orientativos cuando no están documentados. No acredita propiedad, servidumbres ni cantidades de obra y no es una base de construcción."}
JH_Trazabilidad - Origen: Dirección General del Catastro · parcela 9116001QD2091N; Estado: derivado; Capa BIM: Entorno · parcelas catastrales; Mediciones de obra: Excluido; Identificador: CTX-PARCEL-9116001QD2091N; Categoria: Parcela catastral próxima · 9116001QD2091N; ClaseIFC: IfcGeographicElement; EstadoDeInformacion: derivado; DocumentoFuente: {"documentId":"SDGC-CP-9116001QD2091N","title":"Dirección General del Catastro · parcela 9116001QD2091N","date":"2026-09-09","url":"https://www.catastro.hacienda.gob.es/webinspire/index.html","note":"Geometría del servicio vigente consultado el 09/09/2026. La fecha de alta del registro no es una fecha de levantamiento. Contexto recortado a 200 m; no identifica la nueva parcela I-18N."}; IncidenciasPendientes: ["Contexto para lectura del emplazamiento; planta derivada de cartografía, cotas y detalles simplificados. No para construcción ni mediciones de obra.","Las mediciones en el entorno expresan la geometría representada y conservan la precisión de su fuente."]; UsoDeLasMagnitudes: Entorno de coordinación: trazados derivados de las fuentes indicadas por elemento; cotas, espesores, acabados y mobiliario orientativos cuando no están documentados. No acredita propiedad, servidumbres ni cantidades de obra y no es una base de construcción.
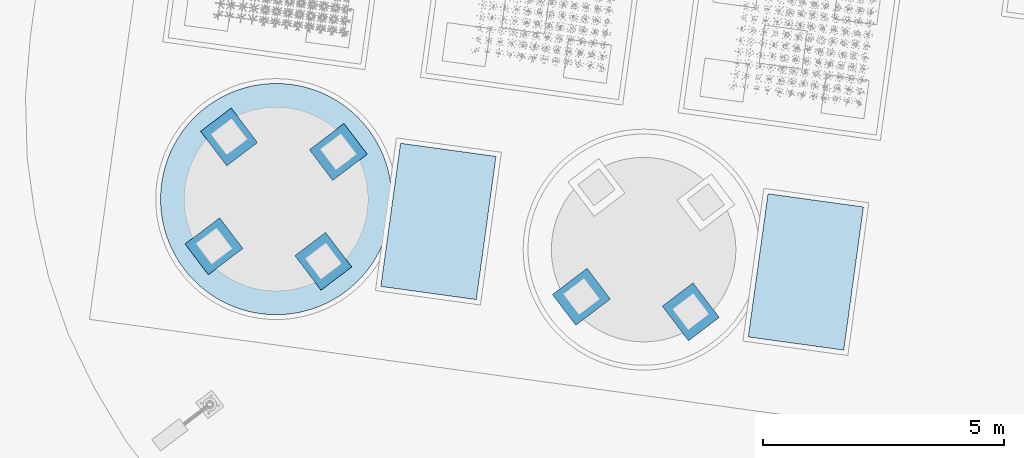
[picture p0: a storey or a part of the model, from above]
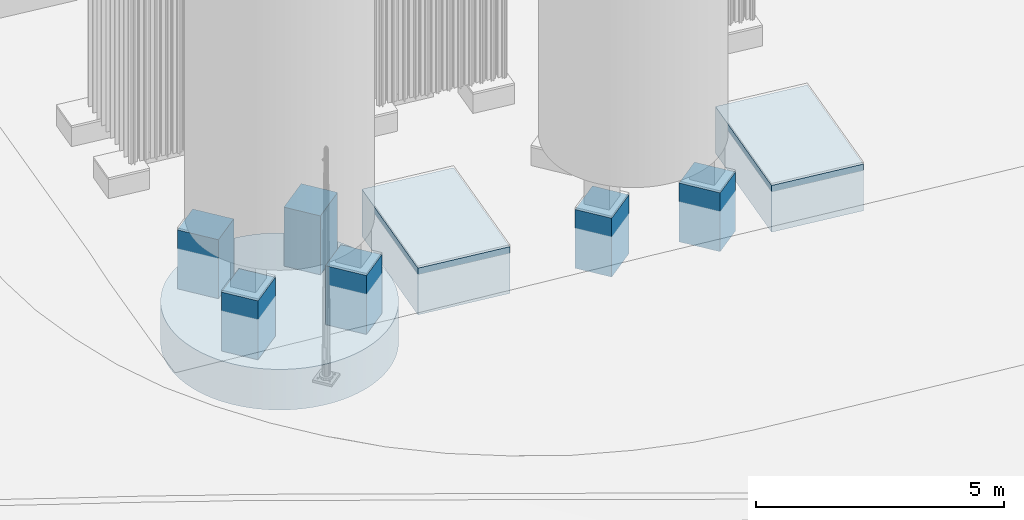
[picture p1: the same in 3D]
Properties of the parts of a building model (IFC4), part 86 of 134

# IfcGeographicElement: Parcela catastral próxima · 9116001QD2091N
JH_CriterioDePosicion - PosicionYEstado: {"Sistema":"ETRS89 / UTM 29N · metros","Origen del modelo":"X 729400 · Y 4301550 · Z 285 m","Alcance":"Hasta 200 m desde el lindero del proyecto; solo exterior de parcela","Planta":"Catastro vigente consultado, contraste con ortofoto PNOA y levantamiento de aceras","Altimetría":"Plano ajustado a 213 puntos XYZ de aceras, extrapolado al resto del contexto; no es un MDT levantado"}
JH_EvidenciaDeMaterial - name: Parcela exterior · suelo de referencia; status: provisional; source: Acabado visual aproximado; no especificación de proyecto.
JH_CapaBIM - IdentificadorCapa: context_parcels; NombreCapa: Entorno · parcelas catastrales; Funcion: Parcela catastral próxima · 9116001QD2091N; VisibilidadInicial: no
JH_EntornoContexto - Estado: derivado; Origen: {"documentId":"SDGC-CP-9116001QD2091N","title":"Dirección General del Catastro · parcela 9116001QD2091N","date":"2026-09-09","url":"https://www.catastro.hacienda.gob.es/webinspire/index.html","note":"Geometría del servicio vigente consultado el 09/09/2026. La fecha de alta del registro no es una fecha de levantamiento. Contexto recortado a 200 m; no identifica la nueva parcela I-18N."}; Posicion: {"Sistema":"ETRS89 / UTM 29N · metros","Origen del modelo":"X 729400 · Y 4301550 · Z 285 m","Alcance":"Hasta 200 m desde el lindero del proyecto; solo exterior de parcela","Planta":"Catastro vigente consultado, contraste con ortofoto PNOA y levantamiento de aceras","Altimetría":"Plano ajustado a 213 puntos XYZ de aceras, extrapolado al resto del contexto; no es un MDT levantado"}; DimensionesSupuestas: [{"label":"Cota exterior","value":"Plano simplificado ajustado a puntos de acera; extrapolación orientativa","unit":""}]; IncluirEnMediciones: no; EsquemaIlustrativo: no; Criterio: Entorno de coordinación: trazados derivados de las fuentes indicadas por elemento; cotas, espesores, acabados y mobiliario orientativos cuando no están documentados. No acredita propiedad, servidumbres ni cantidades de obra y no es una base de construcción.

# IfcGeographicElement: Parcela catastral próxima · 9211601QD2091S
In: Parcela industrial Jinhong
Description: Entorno de coordinación: trazados derivados de las fuentes indicadas por elemento; cotas, espesores, acabados y mobiliario orientativos cuando no están documentados. No acredita propiedad, servidumbres ni cantidades de obra y no es una base de construcción.; PredefinedType: USERDEFINED; Document: Dirección General del Catastro · parcela 9211601QD2091S; Entorno de Expacio Mérida · Catastro INSPIRE, PNOA y levantamiento Berrio; Levantamiento Berrio · parcelas I-27 Vial 3 e I-18 Vial 4; IGN · ortofotografía PNOA de máxima actualidad; Indicación del cliente · entorno de 200 m con aparcamientos y luminarias ilustrativos; Group: BIM · Entorno · parcelas catastrales
JH_InformacionBIM - buildingId: context; buildingName: Entorno exterior de la parcela; level: Exterior · contexto de 200 m; category: Parcela catastral próxima · 9211601QD2091S; ifcClass: IfcGeographicElement; status: derivado; source: {"documentId":"SDGC-CP-9211601QD2091S","title":"Dirección General del Catastro · parcela 9211601QD2091S","date":"2026-09-09","url":"https://www.catastro.hacienda.gob.es/webinspire/index.html","note":"Geometría del servicio vigente consultado el 09/09/2026. La fecha de alta del registro no es una fecha de levantamiento. Contexto recortado a 200 m; no identifica la nueva parcela I-18N."}; material: {"name":"Parcela exterior · suelo de referencia","status":"provisional","source":"Acabado visual aproximado; no especificación de proyecto."}; appearance: {"profileId":"ctx_plot_1","name":"Parcela exterior · suelo de referencia","status":"criterio_visual","basis":"Acabado de contexto orientativo, sin especificación de obra."}; dimensions: {"documented":[],"assumed":[{"label":"Cota exterior","value":"Plano simplificado ajustado a puntos de acera; extrapolación orientativa","unit":""}],"geometry":[{"label":"Extensión representada X","value":329.4889,"unit":"m"},{"label":"Extensión representada Y","value":219.4054,"unit":"m"},{"label":"Extensión representada Z","value":3.7216,"unit":"m"}]}; classification: {"layerId":"context_parcels","layerName":"Entorno · parcelas catastrales","function":"Parcela catastral próxima · 9211601QD2091S"}; visualLayer: {"id":"context_parcels","name":"Entorno · parcelas catastrales","defaultVisible":false}; representationKind: contexto_cartografico_derivado; quantityEligible: no; positioning: {"Sistema":"ETRS89 / UTM 29N · metros","Origen del modelo":"X 729400 · Y 4301550 · Z 285 m","Alcance":"Hasta 200 m desde el lindero del proyecto; solo exterior de parcela","Planta":"Catastro vigente consultado, contraste con ortofoto PNOA y levantamiento de aceras","Altimetría":"Plano ajustado a 213 puntos XYZ de aceras, extrapolado al resto del contexto; no es un MDT levantado"}; issues: ["Contexto para lectura del emplazamiento; planta derivada de cartografía, cotas y detalles simplificados. No para construcción ni mediciones de obra.","Las mediciones en el entorno expresan la geometría representada y conservan la precisión de su fuente."]; cadastralReference: 9211601QD2091S; cadastralRecordBeginLifespan: 2018-04-06T00:00:00; geometryMetrics: {"boundingBoxM":{"min":[-205.839326,-195.916446,-2.031289],"max":[123.649542,23.488931,1.690309]},"extentsM":[329.488868,219.405377,3.721598],"meshSurfaceM2":93834.14775,"meshVolumeM3":3749.482525,"closedSolid":true,"basis":"Entorno de coordinación: trazados derivados de las fuentes indicadas por elemento; cotas, espesores, acabados y mobiliario orientativos cuando no están documentados. No acredita propiedad, servidumbres ni cantidades de obra y no es una base de construcción."}
JH_Trazabilidad - Origen: Dirección General del Catastro · parcela 9211601QD2091S; Estado: derivado; Capa BIM: Entorno · parcelas catastrales; Mediciones de obra: Excluido; Identificador: CTX-PARCEL-9211601QD2091S; Categoria: Parcela catastral próxima · 9211601QD2091S; ClaseIFC: IfcGeographicElement; EstadoDeInformacion: derivado; DocumentoFuente: {"documentId":"SDGC-CP-9211601QD2091S","title":"Dirección General del Catastro · parcela 9211601QD2091S","date":"2026-09-09","url":"https://www.catastro.hacienda.gob.es/webinspire/index.html","note":"Geometría del servicio vigente consultado el 09/09/2026. La fecha de alta del registro no es una fecha de levantamiento. Contexto recortado a 200 m; no identifica la nueva parcela I-18N."}; IncidenciasPendientes: ["Contexto para lectura del emplazamiento; planta derivada de cartografía, cotas y detalles simplificados. No para construcción ni mediciones de obra.","Las mediciones en el entorno expresan la geometría representada y conservan la precisión de su fuente."]; UsoDeLasMagnitudes: Entorno de coordinación: trazados derivados de las fuentes indicadas por elemento; cotas, espesores, acabados y mobiliario orientativos cuando no están documentados. No acredita propiedad, servidumbres ni cantidades de obra y no es una base de construcción.
JH_CriterioDePosicion - PosicionYEstado: {"Sistema":"ETRS89 / UTM 29N · metros","Origen del modelo":"X 729400 · Y 4301550 · Z 285 m","Alcance":"Hasta 200 m desde el lindero del proyecto; solo exterior de parcela","Planta":"Catastro vigente consultado, contraste con ortofoto PNOA y levantamiento de aceras","Altimetría":"Plano ajustado a 213 puntos XYZ de aceras, extrapolado al resto del contexto; no es un MDT levantado"}
JH_EvidenciaDeMaterial - name: Parcela exterior · suelo de referencia; status: provisional; source: Acabado visual aproximado; no especificación de proyecto.
JH_CapaBIM - IdentificadorCapa: context_parcels; NombreCapa: Entorno · parcelas catastrales; Funcion: Parcela catastral próxima · 9211601QD2091S; VisibilidadInicial: no
JH_EntornoContexto - Estado: derivado; Origen: {"documentId":"SDGC-CP-9211601QD2091S","title":"Dirección General del Catastro · parcela 9211601QD2091S","date":"2026-09-09","url":"https://www.catastro.hacienda.gob.es/webinspire/index.html","note":"Geometría del servicio vigente consultado el 09/09/2026. La fecha de alta del registro no es una fecha de levantamiento. Contexto recortado a 200 m; no identifica la nueva parcela I-18N."}; Posicion: {"Sistema":"ETRS89 / UTM 29N · metros","Origen del modelo":"X 729400 · Y 4301550 · Z 285 m","Alcance":"Hasta 200 m desde el lindero del proyecto; solo exterior de parcela","Planta":"Catastro vigente consultado, contraste con ortofoto PNOA y levantamiento de aceras","Altimetría":"Plano ajustado a 213 puntos XYZ de aceras, extrapolado al resto del contexto; no es un MDT levantado"}; DimensionesSupuestas: [{"label":"Cota exterior","value":"Plano simplificado ajustado a puntos de acera; extrapolación orientativa","unit":""}]; IncluirEnMediciones: no; EsquemaIlustrativo: no; Criterio: Entorno de coordinación: trazados derivados de las fuentes indicadas por elemento; cotas, espesores, acabados y mobiliario orientativos cuando no están documentados. No acredita propiedad, servidumbres ni cantidades de obra y no es una base de construcción.

# IfcGeographicElement: Parcela catastral próxima · 9220805QD2092S
In: Parcela industrial Jinhong
Description: Entorno de coordinación: trazados derivados de las fuentes indicadas por elemento; cotas, espesores, acabados y mobiliario orientativos cuando no están documentados. No acredita propiedad, servidumbres ni cantidades de obra y no es una base de construcción.; PredefinedType: USERDEFINED; Document: Dirección General del Catastro · parcela 9220805QD2092S; Entorno de Expacio Mérida · Catastro INSPIRE, PNOA y levantamiento Berrio; Levantamiento Berrio · parcelas I-27 Vial 3 e I-18 Vial 4; IGN · ortofotografía PNOA de máxima actualidad; Indicación del cliente · entorno de 200 m con aparcamientos y luminarias ilustrativos; Group: BIM · Entorno · parcelas catastrales
JH_InformacionBIM - buildingId: context; buildingName: Entorno exterior de la parcela; level: Exterior · contexto de 200 m; category: Parcela catastral próxima · 9220805QD2092S; ifcClass: IfcGeographicElement; status: derivado; source: {"documentId":"SDGC-CP-9220805QD2092S","title":"Dirección General del Catastro · parcela 9220805QD2092S","date":"2026-09-09","url":"https://www.catastro.hacienda.gob.es/webinspire/index.html","note":"Geometría del servicio vigente consultado el 09/09/2026. La fecha de alta del registro no es una fecha de levantamiento. Contexto recortado a 200 m; no identifica la nueva parcela I-18N."}; material: {"name":"Parcela exterior · suelo de referencia","status":"provisional","source":"Acabado visual aproximado; no especificación de proyecto."}; appearance: {"profileId":"ctx_plot_2","name":"Parcela exterior · suelo de referencia","status":"criterio_visual","basis":"Acabado de contexto orientativo, sin especificación de obra."}; dimensions: {"documented":[],"assumed":[{"label":"Cota exterior","value":"Plano simplificado ajustado a puntos de acera; extrapolación orientativa","unit":""}],"geometry":[{"label":"Extensión representada X","value":369.0891,"unit":"m"},{"label":"Extensión representada Y","value":75.6416,"unit":"m"},{"label":"Extensión representada Z","value":4.1759,"unit":"m"}]}; classification: {"layerId":"context_parcels","layerName":"Entorno · parcelas catastrales","function":"Parcela catastral próxima · 9220805QD2092S"}; visualLayer: {"id":"context_parcels","name":"Entorno · parcelas catastrales","defaultVisible":false}; representationKind: contexto_cartografico_derivado; quantityEligible: no; positioning: {"Sistema":"ETRS89 / UTM 29N · metros","Origen del modelo":"X 729400 · Y 4301550 · Z 285 m","Alcance":"Hasta 200 m desde el lindero del proyecto; solo exterior de parcela","Planta":"Catastro vigente consultado, contraste con ortofoto PNOA y levantamiento de aceras","Altimetría":"Plano ajustado a 213 puntos XYZ de aceras, extrapolado al resto del contexto; no es un MDT levantado"}; issues: ["Contexto para lectura del emplazamiento; planta derivada de cartografía, cotas y detalles simplificados. No para construcción ni mediciones de obra.","Las mediciones en el entorno expresan la geometría representada y conservan la precisión de su fuente."]; cadastralReference: 9220805QD2092S; cadastralRecordBeginLifespan: 2018-01-15T00:00:00; geometryMetrics: {"boundingBoxM":{"min":[-102.283209,233.71,-0.125427],"max":[266.80587,309.351583,4.050451]},"extentsM":[369.089079,75.641583,4.175878],"meshSurfaceM2":24005.811123,"meshVolumeM3":957.640301,"closedSolid":true,"basis":"Entorno de coordinación: trazados derivados de las fuentes indicadas por elemento; cotas, espesores, acabados y mobiliario orientativos cuando no están documentados. No acredita propiedad, servidumbres ni cantidades de obra y no es una base de construcción."}
JH_Trazabilidad - Origen: Dirección General del Catastro · parcela 9220805QD2092S; Estado: derivado; Capa BIM: Entorno · parcelas catastrales; Mediciones de obra: Excluido; Identificador: CTX-PARCEL-9220805QD2092S; Categoria: Parcela catastral próxima · 9220805QD2092S; ClaseIFC: IfcGeographicElement; EstadoDeInformacion: derivado; DocumentoFuente: {"documentId":"SDGC-CP-9220805QD2092S","title":"Dirección General del Catastro · parcela 9220805QD2092S","date":"2026-09-09","url":"https://www.catastro.hacienda.gob.es/webinspire/index.html","note":"Geometría del servicio vigente consultado el 09/09/2026. La fecha de alta del registro no es una fecha de levantamiento. Contexto recortado a 200 m; no identifica la nueva parcela I-18N."}; IncidenciasPendientes: ["Contexto para lectura del emplazamiento; planta derivada de cartografía, cotas y detalles simplificados. No para construcción ni mediciones de obra.","Las mediciones en el entorno expresan la geometría representada y conservan la precisión de su fuente."]; UsoDeLasMagnitudes: Entorno de coordinación: trazados derivados de las fuentes indicadas por elemento; cotas, espesores, acabados y mobiliario orientativos cuando no están documentados. No acredita propiedad, servidumbres ni cantidades de obra y no es una base de construcción.
JH_CriterioDePosicion - PosicionYEstado: {"Sistema":"ETRS89 / UTM 29N · metros","Origen del modelo":"X 729400 · Y 4301550 · Z 285 m","Alcance":"Hasta 200 m desde el lindero del proyecto; solo exterior de parcela","Planta":"Catastro vigente consultado, contraste con ortofoto PNOA y levantamiento de aceras","Altimetría":"Plano ajustado a 213 puntos XYZ de aceras, extrapolado al resto del contexto; no es un MDT levantado"}
JH_EvidenciaDeMaterial - name: Parcela exterior · suelo de referencia; status: provisional; source: Acabado visual aproximado; no especificación de proyecto.
JH_CapaBIM - IdentificadorCapa: context_parcels; NombreCapa: Entorno · parcelas catastrales; Funcion: Parcela catastral próxima · 9220805QD2092S; VisibilidadInicial: no
JH_EntornoContexto - Estado: derivado; Origen: {"documentId":"SDGC-CP-9220805QD2092S","title":"Dirección General del Catastro · parcela 9220805QD2092S","date":"2026-09-09","url":"https://www.catastro.hacienda.gob.es/webinspire/index.html","note":"Geometría del servicio vigente consultado el 09/09/2026. La fecha de alta del registro no es una fecha de levantamiento. Contexto recortado a 200 m; no identifica la nueva parcela I-18N."}; Posicion: {"Sistema":"ETRS89 / UTM 29N · metros","Origen del modelo":"X 729400 · Y 4301550 · Z 285 m","Alcance":"Hasta 200 m desde el lindero del proyecto; solo exterior de parcela","Planta":"Catastro vigente consultado, contraste con ortofoto PNOA y levantamiento de aceras","Altimetría":"Plano ajustado a 213 puntos XYZ de aceras, extrapolado al resto del contexto; no es un MDT levantado"}; DimensionesSupuestas: [{"label":"Cota exterior","value":"Plano simplificado ajustado a puntos de acera; extrapolación orientativa","unit":""}]; IncluirEnMediciones: no; EsquemaIlustrativo: no; Criterio: Entorno de coordinación: trazados derivados de las fuentes indicadas por elemento; cotas, espesores, acabados y mobiliario orientativos cuando no están documentados. No acredita propiedad, servidumbres ni cantidades de obra y no es una base de construcción.

# IfcGeographicElement: Parcela catastral próxima · 9516101QD2091N
In: Parcela industrial Jinhong
Description: Entorno de coordinación: trazados derivados de las fuentes indicadas por elemento; cotas, espesores, acabados y mobiliario orientativos cuando no están documentados. No acredita propiedad, servidumbres ni cantidades de obra y no es una base de construcción.; PredefinedType: USERDEFINED; Document: Dirección General del Catastro · parcela 9516101QD2091N; Entorno de Expacio Mérida · Catastro INSPIRE, PNOA y levantamiento Berrio; Levantamiento Berrio · parcelas I-27 Vial 3 e I-18 Vial 4; IGN · ortofotografía PNOA de máxima actualidad; Indicación del cliente · entorno de 200 m con aparcamientos y luminarias ilustrativos; Group: BIM · Entorno · parcelas catastrales
JH_InformacionBIM - buildingId: context; buildingName: Entorno exterior de la parcela; level: Exterior · contexto de 200 m; category: Parcela catastral próxima · 9516101QD2091N; ifcClass: IfcGeographicElement; status: derivado; source: {"documentId":"SDGC-CP-9516101QD2091N","title":"Dirección General del Catastro · parcela 9516101QD2091N","date":"2026-09-09","url":"https://www.catastro.hacienda.gob.es/webinspire/index.html","note":"Geometría del servicio vigente consultado el 09/09/2026. La fecha de alta del registro no es una fecha de levantamiento. Contexto recortado a 200 m; no identifica la nueva parcela I-18N."}; material: {"name":"Parcela exterior · suelo de referencia","status":"provisional","source":"Acabado visual aproximado; no especificación de proyecto."}; appearance: {"profileId":"ctx_plot_3","name":"Parcela exterior · suelo de referencia","status":"criterio_visual","basis":"Acabado de contexto orientativo, sin especificación de obra."}; dimensions: {"documented":[],"assumed":[{"label":"Cota exterior","value":"Plano simplificado ajustado a puntos de acera; extrapolación orientativa","unit":""}],"geometry":[{"label":"Extensión representada X","value":153.0296,"unit":"m"},{"label":"Extensión representada Y","value":166.02,"unit":"m"},{"label":"Extensión representada Z","value":2.1,"unit":"m"}]}; classification: {"layerId":"context_parcels","layerName":"Entorno · parcelas catastrales","function":"Parcela catastral próxima · 9516101QD2091N"}; visualLayer: {"id":"context_parcels","name":"Entorno · parcelas catastrales","defaultVisible":false}; representationKind: contexto_cartografico_derivado; quantityEligible: no; positioning: {"Sistema":"ETRS89 / UTM 29N · metros","Origen del modelo":"X 729400 · Y 4301550 · Z 285 m","Alcance":"Hasta 200 m desde el lindero del proyecto; solo exterior de parcela","Planta":"Catastro vigente consultado, contraste con ortofoto PNOA y levantamiento de aceras","Altimetría":"Plano ajustado a 213 puntos XYZ de aceras, extrapolado al resto del contexto; no es un MDT levantado"}; issues: ["Contexto para lectura del emplazamiento; planta derivada de cartografía, cotas y detalles simplificados. No para construcción ni mediciones de obra.","Las mediciones en el entorno expresan la geometría representada y conservan la precisión de su fuente."]; cadastralReference: 9516101QD2091N; cadastralRecordBeginLifespan: 2018-01-15T00:00:00; geometryMetrics: {"boundingBoxM":{"min":[3.850358,63.17,0.623003],"max":[156.88,229.19,2.723038]},"extentsM":[153.029642,166.02,2.100035],"meshSurfaceM2":34798.797861,"meshVolumeM3":1390.031092,"closedSolid":true,"basis":"Entorno de coordinación: trazados derivados de las fuentes indicadas por elemento; cotas, espesores, acabados y mobiliario orientativos cuando no están documentados. No acredita propiedad, servidumbres ni cantidades de obra y no es una base de construcción."}
JH_Trazabilidad - Origen: Dirección General del Catastro · parcela 9516101QD2091N; Estado: derivado; Capa BIM: Entorno · parcelas catastrales; Mediciones de obra: Excluido; Identificador: CTX-PARCEL-9516101QD2091N; Categoria: Parcela catastral próxima · 9516101QD2091N; ClaseIFC: IfcGeographicElement; EstadoDeInformacion: derivado; DocumentoFuente: {"documentId":"SDGC-CP-9516101QD2091N","title":"Dirección General del Catastro · parcela 9516101QD2091N","date":"2026-09-09","url":"https://www.catastro.hacienda.gob.es/webinspire/index.html","note":"Geometría del servicio vigente consultado el 09/09/2026. La fecha de alta del registro no es una fecha de levantamiento. Contexto recortado a 200 m; no identifica la nueva parcela I-18N."}; IncidenciasPendientes: ["Contexto para lectura del emplazamiento; planta derivada de cartografía, cotas y detalles simplificados. No para construcción ni mediciones de obra.","Las mediciones en el entorno expresan la geometría representada y conservan la precisión de su fuente."]; UsoDeLasMagnitudes: Entorno de coordinación: trazados derivados de las fuentes indicadas por elemento; cotas, espesores, acabados y mobiliario orientativos cuando no están documentados. No acredita propiedad, servidumbres ni cantidades de obra y no es una base de construcción.
JH_CriterioDePosicion - PosicionYEstado: {"Sistema":"ETRS89 / UTM 29N · metros","Origen del modelo":"X 729400 · Y 4301550 · Z 285 m","Alcance":"Hasta 200 m desde el lindero del proyecto; solo exterior de parcela","Planta":"Catastro vigente consultado, contraste con ortofoto PNOA y levantamiento de aceras","Altimetría":"Plano ajustado a 213 puntos XYZ de aceras, extrapolado al resto del contexto; no es un MDT levantado"}
JH_EvidenciaDeMaterial - name: Parcela exterior · suelo de referencia; status: provisional; source: Acabado visual aproximado; no especificación de proyecto.
JH_CapaBIM - IdentificadorCapa: context_parcels; NombreCapa: Entorno · parcelas catastrales; Funcion: Parcela catastral próxima · 9516101QD2091N; VisibilidadInicial: no
JH_EntornoContexto - Estado: derivado; Origen: {"documentId":"SDGC-CP-9516101QD2091N","title":"Dirección General del Catastro · parcela 9516101QD2091N","date":"2026-09-09","url":"https://www.catastro.hacienda.gob.es/webinspire/index.html","note":"Geometría del servicio vigente consultado el 09/09/2026. La fecha de alta del registro no es una fecha de levantamiento. Contexto recortado a 200 m; no identifica la nueva parcela I-18N."}; Posicion: {"Sistema":"ETRS89 / UTM 29N · metros","Origen del modelo":"X 729400 · Y 4301550 · Z 285 m","Alcance":"Hasta 200 m desde el lindero del proyecto; solo exterior de parcela","Planta":"Catastro vigente consultado, contraste con ortofoto PNOA y levantamiento de aceras","Altimetría":"Plano ajustado a 213 puntos XYZ de aceras, extrapolado al resto del contexto; no es un MDT levantado"}; DimensionesSupuestas: [{"label":"Cota exterior","value":"Plano simplificado ajustado a puntos de acera; extrapolación orientativa","unit":""}]; IncluirEnMediciones: no; EsquemaIlustrativo: no; Criterio: Entorno de coordinación: trazados derivados de las fuentes indicadas por elemento; cotas, espesores, acabados y mobiliario orientativos cuando no están documentados. No acredita propiedad, servidumbres ni cantidades de obra y no es una base de construcción.

# IfcGeographicElement: Parcela catastral próxima · 9516102QD2091N
In: Parcela industrial Jinhong
Description: Entorno de coordinación: trazados derivados de las fuentes indicadas por elemento; cotas, espesores, acabados y mobiliario orientativos cuando no están documentados. No acredita propiedad, servidumbres ni cantidades de obra y no es una base de construcción.; PredefinedType: USERDEFINED; Document: Dirección General del Catastro · parcela 9516102QD2091N; Entorno de Expacio Mérida · Catastro INSPIRE, PNOA y levantamiento Berrio; Levantamiento Berrio · parcelas I-27 Vial 3 e I-18 Vial 4; IGN · ortofotografía PNOA de máxima actualidad; Indicación del cliente · entorno de 200 m con aparcamientos y luminarias ilustrativos; Group: BIM · Entorno · parcelas catastrales
JH_InformacionBIM - buildingId: context; buildingName: Entorno exterior de la parcela; level: Exterior · contexto de 200 m; category: Parcela catastral próxima · 9516102QD2091N; ifcClass: IfcGeographicElement; status: derivado; source: {"documentId":"SDGC-CP-9516102QD2091N","title":"Dirección General del Catastro · parcela 9516102QD2091N","date":"2026-09-09","url":"https://www.catastro.hacienda.gob.es/webinspire/index.html","note":"Geometría del servicio vigente consultado el 09/09/2026. La fecha de alta del registro no es una fecha de levantamiento. Contexto recortado a 200 m; no identifica la nueva parcela I-18N."}; material: {"name":"Parcela exterior · suelo de referencia","status":"provisional","source":"Acabado visual aproximado; no especificación de proyecto."}; appearance: {"profileId":"ctx_plot_0","name":"Parcela exterior · suelo de referencia","status":"criterio_visual","basis":"Acabado de contexto orientativo, sin especificación de obra."}; dimensions: {"documented":[],"assumed":[{"label":"Cota exterior","value":"Plano simplificado ajustado a puntos de acera; extrapolación orientativa","unit":""}],"geometry":[{"label":"Extensión representada X","value":131.69,"unit":"m"},{"label":"Extensión representada Y","value":166.79,"unit":"m"},{"label":"Extensión representada Z","value":1.8768,"unit":"m"}]}; classification: {"layerId":"context_parcels","layerName":"Entorno · parcelas catastrales","function":"Parcela catastral próxima · 9516102QD2091N"}; visualLayer: {"id":"context_parcels","name":"Entorno · parcelas catastrales","defaultVisible":false}; representationKind: contexto_cartografico_derivado; quantityEligible: no; positioning: {"Sistema":"ETRS89 / UTM 29N · metros","Origen del modelo":"X 729400 · Y 4301550 · Z 285 m","Alcance":"Hasta 200 m desde el lindero del proyecto; solo exterior de parcela","Planta":"Catastro vigente consultado, contraste con ortofoto PNOA y levantamiento de aceras","Altimetría":"Plano ajustado a 213 puntos XYZ de aceras, extrapolado al resto del contexto; no es un MDT levantado"}; issues: ["Contexto para lectura del emplazamiento; planta derivada de cartografía, cotas y detalles simplificados. No para construcción ni mediciones de obra.","Las mediciones en el entorno expresan la geometría representada y conservan la precisión de su fuente."]; cadastralReference: 9516102QD2091N; cadastralRecordBeginLifespan: 2018-01-15T00:00:00; geometryMetrics: {"boundingBoxM":{"min":[136.79,46.98,2.012737],"max":[268.48,213.77,3.889562]},"extentsM":[131.69,166.79,1.876825],"meshSurfaceM2":35618.318566,"meshVolumeM3":1422.94362,"closedSolid":true,"basis":"Entorno de coordinación: trazados derivados de las fuentes indicadas por elemento; cotas, espesores, acabados y mobiliario orientativos cuando no están documentados. No acredita propiedad, servidumbres ni cantidades de obra y no es una base de construcción."}
JH_Trazabilidad - Origen: Dirección General del Catastro · parcela 9516102QD2091N; Estado: derivado; Capa BIM: Entorno · parcelas catastrales; Mediciones de obra: Excluido; Identificador: CTX-PARCEL-9516102QD2091N; Categoria: Parcela catastral próxima · 9516102QD2091N; ClaseIFC: IfcGeographicElement; EstadoDeInformacion: derivado; DocumentoFuente: {"documentId":"SDGC-CP-9516102QD2091N","title":"Dirección General del Catastro · parcela 9516102QD2091N","date":"2026-09-09","url":"https://www.catastro.hacienda.gob.es/webinspire/index.html","note":"Geometría del servicio vigente consultado el 09/09/2026. La fecha de alta del registro no es una fecha de levantamiento. Contexto recortado a 200 m; no identifica la nueva parcela I-18N."}; IncidenciasPendientes: ["Contexto para lectura del emplazamiento; planta derivada de cartografía, cotas y detalles simplificados. No para construcción ni mediciones de obra.","Las mediciones en el entorno expresan la geometría representada y conservan la precisión de su fuente."]; UsoDeLasMagnitudes: Entorno de coordinación: trazados derivados de las fuentes indicadas por elemento; cotas, espesores, acabados y mobiliario orientativos cuando no están documentados. No acredita propiedad, servidumbres ni cantidades de obra y no es una base de construcción.
JH_CriterioDePosicion - PosicionYEstado: {"Sistema":"ETRS89 / UTM 29N · metros","Origen del modelo":"X 729400 · Y 4301550 · Z 285 m","Alcance":"Hasta 200 m desde el lindero del proyecto; solo exterior de parcela","Planta":"Catastro vigente consultado, contraste con ortofoto PNOA y levantamiento de aceras","Altimetría":"Plano ajustado a 213 puntos XYZ de aceras, extrapolado al resto del contexto; no es un MDT levantado"}
JH_EvidenciaDeMaterial - name: Parcela exterior · suelo de referencia; status: provisional; source: Acabado visual aproximado; no especificación de proyecto.
JH_CapaBIM - IdentificadorCapa: context_parcels; NombreCapa: Entorno · parcelas catastrales; Funcion: Parcela catastral próxima · 9516102QD2091N; VisibilidadInicial: no
JH_EntornoContexto - Estado: derivado; Origen: {"documentId":"SDGC-CP-9516102QD2091N","title":"Dirección General del Catastro · parcela 9516102QD2091N","date":"2026-09-09","url":"https://www.catastro.hacienda.gob.es/webinspire/index.html","note":"Geometría del servicio vigente consultado el 09/09/2026. La fecha de alta del registro no es una fecha de levantamiento. Contexto recortado a 200 m; no identifica la nueva parcela I-18N."}; Posicion: {"Sistema":"ETRS89 / UTM 29N · metros","Origen del modelo":"X 729400 · Y 4301550 · Z 285 m","Alcance":"Hasta 200 m desde el lindero del proyecto; solo exterior de parcela","Planta":"Catastro vigente consultado, contraste con ortofoto PNOA y levantamiento de aceras","Altimetría":"Plano ajustado a 213 puntos XYZ de aceras, extrapolado al resto del contexto; no es un MDT levantado"}; DimensionesSupuestas: [{"label":"Cota exterior","value":"Plano simplificado ajustado a puntos de acera; extrapolación orientativa","unit":""}]; IncluirEnMediciones: no; EsquemaIlustrativo: no; Criterio: Entorno de coordinación: trazados derivados de las fuentes indicadas por elemento; cotas, espesores, acabados y mobiliario orientativos cuando no están documentados. No acredita propiedad, servidumbres ni cantidades de obra y no es una base de construcción.

# IfcGeographicElement: Parcela catastral próxima · 9516103QD2091N
In: Parcela industrial Jinhong
Description: Entorno de coordinación: trazados derivados de las fuentes indicadas por elemento; cotas, espesores, acabados y mobiliario orientativos cuando no están documentados. No acredita propiedad, servidumbres ni cantidades de obra y no es una base de construcción.; PredefinedType: USERDEFINED; Document: Dirección General del Catastro · parcela 9516103QD2091N; Entorno de Expacio Mérida · Catastro INSPIRE, PNOA y levantamiento Berrio; Levantamiento Berrio · parcelas I-27 Vial 3 e I-18 Vial 4; IGN · ortofotografía PNOA de máxima actualidad; Indicación del cliente · entorno de 200 m con aparcamientos y luminarias ilustrativos; Group: BIM · Entorno · parcelas catastrales
JH_InformacionBIM - buildingId: context; buildingName: Entorno exterior de la parcela; level: Exterior · contexto de 200 m; category: Parcela catastral próxima · 9516103QD2091N; ifcClass: IfcGeographicElement; status: derivado; source: {"documentId":"SDGC-CP-9516103QD2091N","title":"Dirección General del Catastro · parcela 9516103QD2091N","date":"2026-09-09","url":"https://www.catastro.hacienda.gob.es/webinspire/index.html","note":"Geometría del servicio vigente consultado el 09/09/2026. La fecha de alta del registro no es una fecha de levantamiento. Contexto recortado a 200 m; no identifica la nueva parcela I-18N."}; material: {"name":"Parcela exterior · suelo de referencia","status":"provisional","source":"Acabado visual aproximado; no especificación de proyecto."}; appearance: {"profileId":"ctx_plot_1","name":"Parcela exterior · suelo de referencia","status":"criterio_visual","basis":"Acabado de contexto orientativo, sin especificación de obra."}; dimensions: {"documented":[],"assumed":[{"label":"Cota exterior","value":"Plano simplificado ajustado a puntos de acera; extrapolación orientativa","unit":""}],"geometry":[{"label":"Extensión representada X","value":129.1232,"unit":"m"},{"label":"Extensión representada Y","value":73.5895,"unit":"m"},{"label":"Extensión representada Z","value":1.6627,"unit":"m"}]}; classification: {"layerId":"context_parcels","layerName":"Entorno · parcelas catastrales","function":"Parcela catastral próxima · 9516103QD2091N"}; visualLayer: {"id":"context_parcels","name":"Entorno · parcelas catastrales","defaultVisible":false}; representationKind: contexto_cartografico_derivado; quantityEligible: no; positioning: {"Sistema":"ETRS89 / UTM 29N · metros","Origen del modelo":"X 729400 · Y 4301550 · Z 285 m","Alcance":"Hasta 200 m desde el lindero del proyecto; solo exterior de parcela","Planta":"Catastro vigente consultado, contraste con ortofoto PNOA y levantamiento de aceras","Altimetría":"Plano ajustado a 213 puntos XYZ de aceras, extrapolado al resto del contexto; no es un MDT levantado"}; issues: ["Contexto para lectura del emplazamiento; planta derivada de cartografía, cotas y detalles simplificados. No para construcción ni mediciones de obra.","Las mediciones en el entorno expresan la geometría representada y conservan la precisión de su fuente."]; cadastralReference: 9516103QD2091N; cadastralRecordBeginLifespan: 2018-01-15T00:00:00; geometryMetrics: {"boundingBoxM":{"min":[128.906774,-10.419536,1.765558],"max":[258.03,63.17,3.428266]},"extentsM":[129.123226,73.589536,1.662708],"meshSurfaceM2":14658.353794,"meshVolumeM3":585.14383,"closedSolid":true,"basis":"Entorno de coordinación: trazados derivados de las fuentes indicadas por elemento; cotas, espesores, acabados y mobiliario orientativos cuando no están documentados. No acredita propiedad, servidumbres ni cantidades de obra y no es una base de construcción."}
JH_Trazabilidad - Origen: Dirección General del Catastro · parcela 9516103QD2091N; Estado: derivado; Capa BIM: Entorno · parcelas catastrales; Mediciones de obra: Excluido; Identificador: CTX-PARCEL-9516103QD2091N; Categoria: Parcela catastral próxima · 9516103QD2091N; ClaseIFC: IfcGeographicElement; EstadoDeInformacion: derivado; DocumentoFuente: {"documentId":"SDGC-CP-9516103QD2091N","title":"Dirección General del Catastro · parcela 9516103QD2091N","date":"2026-09-09","url":"https://www.catastro.hacienda.gob.es/webinspire/index.html","note":"Geometría del servicio vigente consultado el 09/09/2026. La fecha de alta del registro no es una fecha de levantamiento. Contexto recortado a 200 m; no identifica la nueva parcela I-18N."}; IncidenciasPendientes: ["Contexto para lectura del emplazamiento; planta derivada de cartografía, cotas y detalles simplificados. No para construcción ni mediciones de obra.","Las mediciones en el entorno expresan la geometría representada y conservan la precisión de su fuente."]; UsoDeLasMagnitudes: Entorno de coordinación: trazados derivados de las fuentes indicadas por elemento; cotas, espesores, acabados y mobiliario orientativos cuando no están documentados. No acredita propiedad, servidumbres ni cantidades de obra y no es una base de construcción.
JH_CriterioDePosicion - PosicionYEstado: {"Sistema":"ETRS89 / UTM 29N · metros","Origen del modelo":"X 729400 · Y 4301550 · Z 285 m","Alcance":"Hasta 200 m desde el lindero del proyecto; solo exterior de parcela","Planta":"Catastro vigente consultado, contraste con ortofoto PNOA y levantamiento de aceras","Altimetría":"Plano ajustado a 213 puntos XYZ de aceras, extrapolado al resto del contexto; no es un MDT levantado"}
JH_EvidenciaDeMaterial - name: Parcela exterior · suelo de referencia; status: provisional; source: Acabado visual aproximado; no especificación de proyecto.
JH_CapaBIM - IdentificadorCapa: context_parcels; NombreCapa: Entorno · parcelas catastrales; Funcion: Parcela catastral próxima · 9516103QD2091N; VisibilidadInicial: no
JH_EntornoContexto - Estado: derivado; Origen: {"documentId":"SDGC-CP-9516103QD2091N","title":"Dirección General del Catastro · parcela 9516103QD2091N","date":"2026-09-09","url":"https://www.catastro.hacienda.gob.es/webinspire/index.html","note":"Geometría del servicio vigente consultado el 09/09/2026. La fecha de alta del registro no es una fecha de levantamiento. Contexto recortado a 200 m; no identifica la nueva parcela I-18N."}; Posicion: {"Sistema":"ETRS89 / UTM 29N · metros","Origen del modelo":"X 729400 · Y 4301550 · Z 285 m","Alcance":"Hasta 200 m desde el lindero del proyecto; solo exterior de parcela","Planta":"Catastro vigente consultado, contraste con ortofoto PNOA y levantamiento de aceras","Altimetría":"Plano ajustado a 213 puntos XYZ de aceras, extrapolado al resto del contexto; no es un MDT levantado"}; DimensionesSupuestas: [{"label":"Cota exterior","value":"Plano simplificado ajustado a puntos de acera; extrapolación orientativa","unit":""}]; IncluirEnMediciones: no; EsquemaIlustrativo: no; Criterio: Entorno de coordinación: trazados derivados de las fuentes indicadas por elemento; cotas, espesores, acabados y mobiliario orientativos cuando no están documentados. No acredita propiedad, servidumbres ni cantidades de obra y no es una base de construcción.

# IfcGeographicElement: Parcela catastral próxima · 9713501QD2091S
In: Parcela industrial Jinhong
Description: Entorno de coordinación: trazados derivados de las fuentes indicadas por elemento; cotas, espesores, acabados y mobiliario orientativos cuando no están documentados. No acredita propiedad, servidumbres ni cantidades de obra y no es una base de construcción.; PredefinedType: USERDEFINED; Document: Dirección General del Catastro · parcela 9713501QD2091S; Entorno de Expacio Mérida · Catastro INSPIRE, PNOA y levantamiento Berrio; Levantamiento Berrio · parcelas I-27 Vial 3 e I-18 Vial 4; IGN · ortofotografía PNOA de máxima actualidad; Indicación del cliente · entorno de 200 m con aparcamientos y luminarias ilustrativos; Group: BIM · Entorno · parcelas catastrales
JH_InformacionBIM - buildingId: context; buildingName: Entorno exterior de la parcela; level: Exterior · contexto de 200 m; category: Parcela catastral próxima · 9713501QD2091S; ifcClass: IfcGeographicElement; status: derivado; source: {"documentId":"SDGC-CP-9713501QD2091S","title":"Dirección General del Catastro · parcela 9713501QD2091S","date":"2026-09-09","url":"https://www.catastro.hacienda.gob.es/webinspire/index.html","note":"Geometría del servicio vigente consultado el 09/09/2026. La fecha de alta del registro no es una fecha de levantamiento. Contexto recortado a 200 m; no identifica la nueva parcela I-18N."}; material: {"name":"Parcela exterior · suelo de referencia","status":"provisional","source":"Acabado visual aproximado; no especificación de proyecto."}; appearance: {"profileId":"ctx_plot_3","name":"Parcela exterior · suelo de referencia","status":"criterio_visual","basis":"Acabado de contexto orientativo, sin especificación de obra."}; dimensions: {"documented":[],"assumed":[{"label":"Cota exterior","value":"Plano simplificado ajustado a puntos de acera; extrapolación orientativa","unit":""}],"geometry":[{"label":"Extensión representada X","value":43.5349,"unit":"m"},{"label":"Extensión representada Y","value":85.6708,"unit":"m"},{"label":"Extensión representada Z","value":0.7959,"unit":"m"}]}; classification: {"layerId":"context_parcels","layerName":"Entorno · parcelas catastrales","function":"Parcela catastral próxima · 9713501QD2091S"}; visualLayer: {"id":"context_parcels","name":"Entorno · parcelas catastrales","defaultVisible":false}; representationKind: contexto_cartografico_derivado; quantityEligible: no; positioning: {"Sistema":"ETRS89 / UTM 29N · metros","Origen del modelo":"X 729400 · Y 4301550 · Z 285 m","Alcance":"Hasta 200 m desde el lindero del proyecto; solo exterior de parcela","Planta":"Catastro vigente consultado, contraste con ortofoto PNOA y levantamiento de aceras","Altimetría":"Plano ajustado a 213 puntos XYZ de aceras, extrapolado al resto del contexto; no es un MDT levantado"}; issues: ["Contexto para lectura del emplazamiento; planta derivada de cartografía, cotas y detalles simplificados. No para construcción ni mediciones de obra.","Las mediciones en el entorno expresan la geometría representada y conservan la precisión de su fuente."]; cadastralReference: 9713501QD2091S; cadastralRecordBeginLifespan: 2018-01-15T00:00:00; geometryMetrics: {"boundingBoxM":{"min":[275.359065,-129.321239,3.074913],"max":[318.893932,-43.650429,3.870839]},"extentsM":[43.534867,85.67081,0.795926],"meshSurfaceM2":3804.172875,"meshVolumeM3":151.479404,"closedSolid":true,"basis":"Entorno de coordinación: trazados derivados de las fuentes indicadas por elemento; cotas, espesores, acabados y mobiliario orientativos cuando no están documentados. No acredita propiedad, servidumbres ni cantidades de obra y no es una base de construcción."}
JH_Trazabilidad - Origen: Dirección General del Catastro · parcela 9713501QD2091S; Estado: derivado; Capa BIM: Entorno · parcelas catastrales; Mediciones de obra: Excluido; Identificador: CTX-PARCEL-9713501QD2091S; Categoria: Parcela catastral próxima · 9713501QD2091S; ClaseIFC: IfcGeographicElement; EstadoDeInformacion: derivado; DocumentoFuente: {"documentId":"SDGC-CP-9713501QD2091S","title":"Dirección General del Catastro · parcela 9713501QD2091S","date":"2026-09-09","url":"https://www.catastro.hacienda.gob.es/webinspire/index.html","note":"Geometría del servicio vigente consultado el 09/09/2026. La fecha de alta del registro no es una fecha de levantamiento. Contexto recortado a 200 m; no identifica la nueva parcela I-18N."}; IncidenciasPendientes: ["Contexto para lectura del emplazamiento; planta derivada de cartografía, cotas y detalles simplificados. No para construcción ni mediciones de obra.","Las mediciones en el entorno expresan la geometría representada y conservan la precisión de su fuente."]; UsoDeLasMagnitudes: Entorno de coordinación: trazados derivados de las fuentes indicadas por elemento; cotas, espesores, acabados y mobiliario orientativos cuando no están documentados. No acredita propiedad, servidumbres ni cantidades de obra y no es una base de construcción.
JH_CriterioDePosicion - PosicionYEstado: {"Sistema":"ETRS89 / UTM 29N · metros","Origen del modelo":"X 729400 · Y 4301550 · Z 285 m","Alcance":"Hasta 200 m desde el lindero del proyecto; solo exterior de parcela","Planta":"Catastro vigente consultado, contraste con ortofoto PNOA y levantamiento de aceras","Altimetría":"Plano ajustado a 213 puntos XYZ de aceras, extrapolado al resto del contexto; no es un MDT levantado"}
JH_EvidenciaDeMaterial - name: Parcela exterior · suelo de referencia; status: provisional; source: Acabado visual aproximado; no especificación de proyecto.
JH_CapaBIM - IdentificadorCapa: context_parcels; NombreCapa: Entorno · parcelas catastrales; Funcion: Parcela catastral próxima · 9713501QD2091S; VisibilidadInicial: no
JH_EntornoContexto - Estado: derivado; Origen: {"documentId":"SDGC-CP-9713501QD2091S","title":"Dirección General del Catastro · parcela 9713501QD2091S","date":"2026-09-09","url":"https://www.catastro.hacienda.gob.es/webinspire/index.html","note":"Geometría del servicio vigente consultado el 09/09/2026. La fecha de alta del registro no es una fecha de levantamiento. Contexto recortado a 200 m; no identifica la nueva parcela I-18N."}; Posicion: {"Sistema":"ETRS89 / UTM 29N · metros","Origen del modelo":"X 729400 · Y 4301550 · Z 285 m","Alcance":"Hasta 200 m desde el lindero del proyecto; solo exterior de parcela","Planta":"Catastro vigente consultado, contraste con ortofoto PNOA y levantamiento de aceras","Altimetría":"Plano ajustado a 213 puntos XYZ de aceras, extrapolado al resto del contexto; no es un MDT levantado"}; DimensionesSupuestas: [{"label":"Cota exterior","value":"Plano simplificado ajustado a puntos de acera; extrapolación orientativa","unit":""}]; IncluirEnMediciones: no; EsquemaIlustrativo: no; Criterio: Entorno de coordinación: trazados derivados de las fuentes indicadas por elemento; cotas, espesores, acabados y mobiliario orientativos cuando no están documentados. No acredita propiedad, servidumbres ni cantidades de obra y no es una base de construcción.

# IfcGeographicElement: Parcela catastral próxima · 9716501QD2091N
In: Parcela industrial Jinhong
Description: Entorno de coordinación: trazados derivados de las fuentes indicadas por elemento; cotas, espesores, acabados y mobiliario orientativos cuando no están documentados. No acredita propiedad, servidumbres ni cantidades de obra y no es una base de construcción.; PredefinedType: USERDEFINED; Document: Dirección General del Catastro · parcela 9716501QD2091N; Entorno de Expacio Mérida · Catastro INSPIRE, PNOA y levantamiento Berrio; Levantamiento Berrio · parcelas I-27 Vial 3 e I-18 Vial 4; IGN · ortofotografía PNOA de máxima actualidad; Indicación del cliente · entorno de 200 m con aparcamientos y luminarias ilustrativos; Group: BIM · Entorno · parcelas catastrales
JH_InformacionBIM - buildingId: context; buildingName: Entorno exterior de la parcela; level: Exterior · contexto de 200 m; category: Parcela catastral próxima · 9716501QD2091N; ifcClass: IfcGeographicElement; status: derivado; source: {"documentId":"SDGC-CP-9716501QD2091N","title":"Dirección General del Catastro · parcela 9716501QD2091N","date":"2026-09-09","url":"https://www.catastro.hacienda.gob.es/webinspire/index.html","note":"Geometría del servicio vigente consultado el 09/09/2026. La fecha de alta del registro no es una fecha de levantamiento. Contexto recortado a 200 m; no identifica la nueva parcela I-18N."}; material: {"name":"Parcela exterior · suelo de referencia","status":"provisional","source":"Acabado visual aproximado; no especificación de proyecto."}; appearance: {"profileId":"ctx_plot_0","name":"Parcela exterior · suelo de referencia","status":"criterio_visual","basis":"Acabado de contexto orientativo, sin especificación de obra."}; dimensions: {"documented":[],"assumed":[{"label":"Cota exterior","value":"Plano simplificado ajustado a puntos de acera; extrapolación orientativa","unit":""}],"geometry":[{"label":"Extensión representada X","value":130.4223,"unit":"m"},{"label":"Extensión representada Y","value":172.4911,"unit":"m"},{"label":"Extensión representada Z","value":1.9599,"unit":"m"}]}; classification: {"layerId":"context_parcels","layerName":"Entorno · parcelas catastrales","function":"Parcela catastral próxima · 9716501QD2091N"}; visualLayer: {"id":"context_parcels","name":"Entorno · parcelas catastrales","defaultVisible":false}; representationKind: contexto_cartografico_derivado; quantityEligible: no; positioning: {"Sistema":"ETRS89 / UTM 29N · metros","Origen del modelo":"X 729400 · Y 4301550 · Z 285 m","Alcance":"Hasta 200 m desde el lindero del proyecto; solo exterior de parcela","Planta":"Catastro vigente consultado, contraste con ortofoto PNOA y levantamiento de aceras","Altimetría":"Plano ajustado a 213 puntos XYZ de aceras, extrapolado al resto del contexto; no es un MDT levantado"}; issues: ["Contexto para lectura del emplazamiento; planta derivada de cartografía, cotas y detalles simplificados. No para construcción ni mediciones de obra.","Las mediciones en el entorno expresan la geometría representada y conservan la precisión de su fuente."]; cadastralReference: 9716501QD2091N; cadastralRecordBeginLifespan: 2011-10-20T00:00:00; geometryMetrics: {"boundingBoxM":{"min":[119.247716,-197.331588,1.118645],"max":[249.669978,-24.84046,3.078536]},"extentsM":[130.422262,172.491128,1.959891],"meshSurfaceM2":35390.145249,"meshVolumeM3":1413.828126,"closedSolid":true,"basis":"Entorno de coordinación: trazados derivados de las fuentes indicadas por elemento; cotas, espesores, acabados y mobiliario orientativos cuando no están documentados. No acredita propiedad, servidumbres ni cantidades de obra y no es una base de construcción."}
JH_Trazabilidad - Origen: Dirección General del Catastro · parcela 9716501QD2091N; Estado: derivado; Capa BIM: Entorno · parcelas catastrales; Mediciones de obra: Excluido; Identificador: CTX-PARCEL-9716501QD2091N; Categoria: Parcela catastral próxima · 9716501QD2091N; ClaseIFC: IfcGeographicElement; EstadoDeInformacion: derivado; DocumentoFuente: {"documentId":"SDGC-CP-9716501QD2091N","title":"Dirección General del Catastro · parcela 9716501QD2091N","date":"2026-09-09","url":"https://www.catastro.hacienda.gob.es/webinspire/index.html","note":"Geometría del servicio vigente consultado el 09/09/2026. La fecha de alta del registro no es una fecha de levantamiento. Contexto recortado a 200 m; no identifica la nueva parcela I-18N."}; IncidenciasPendientes: ["Contexto para lectura del emplazamiento; planta derivada de cartografía, cotas y detalles simplificados. No para construcción ni mediciones de obra.","Las mediciones en el entorno expresan la geometría representada y conservan la precisión de su fuente."]; UsoDeLasMagnitudes: Entorno de coordinación: trazados derivados de las fuentes indicadas por elemento; cotas, espesores, acabados y mobiliario orientativos cuando no están documentados. No acredita propiedad, servidumbres ni cantidades de obra y no es una base de construcción.
JH_CriterioDePosicion - PosicionYEstado: {"Sistema":"ETRS89 / UTM 29N · metros","Origen del modelo":"X 729400 · Y 4301550 · Z 285 m","Alcance":"Hasta 200 m desde el lindero del proyecto; solo exterior de parcela","Planta":"Catastro vigente consultado, contraste con ortofoto PNOA y levantamiento de aceras","Altimetría":"Plano ajustado a 213 puntos XYZ de aceras, extrapolado al resto del contexto; no es un MDT levantado"}
JH_EvidenciaDeMaterial - name: Parcela exterior · suelo de referencia; status: provisional; source: Acabado visual aproximado; no especificación de proyecto.
JH_CapaBIM - IdentificadorCapa: context_parcels; NombreCapa: Entorno · parcelas catastrales; Funcion: Parcela catastral próxima · 9716501QD2091N; VisibilidadInicial: no
JH_EntornoContexto - Estado: derivado; Origen: {"documentId":"SDGC-CP-9716501QD2091N","title":"Dirección General del Catastro · parcela 9716501QD2091N","date":"2026-09-09","url":"https://www.catastro.hacienda.gob.es/webinspire/index.html","note":"Geometría del servicio vigente consultado el 09/09/2026. La fecha de alta del registro no es una fecha de levantamiento. Contexto recortado a 200 m; no identifica la nueva parcela I-18N."}; Posicion: {"Sistema":"ETRS89 / UTM 29N · metros","Origen del modelo":"X 729400 · Y 4301550 · Z 285 m","Alcance":"Hasta 200 m desde el lindero del proyecto; solo exterior de parcela","Planta":"Catastro vigente consultado, contraste con ortofoto PNOA y levantamiento de aceras","Altimetría":"Plano ajustado a 213 puntos XYZ de aceras, extrapolado al resto del contexto; no es un MDT levantado"}; DimensionesSupuestas: [{"label":"Cota exterior","value":"Plano simplificado ajustado a puntos de acera; extrapolación orientativa","unit":""}]; IncluirEnMediciones: no; EsquemaIlustrativo: no; Criterio: Entorno de coordinación: trazados derivados de las fuentes indicadas por elemento; cotas, espesores, acabados y mobiliario orientativos cuando no están documentados. No acredita propiedad, servidumbres ni cantidades de obra y no es una base de construcción.

# IfcGeographicElement: Parcela catastral próxima · 9716701QD2091N
In: Parcela industrial Jinhong
Description: Entorno de coordinación: trazados derivados de las fuentes indicadas por elemento; cotas, espesores, acabados y mobiliario orientativos cuando no están documentados. No acredita propiedad, servidumbres ni cantidades de obra y no es una base de construcción.; PredefinedType: USERDEFINED; Document: Dirección General del Catastro · parcela 9716701QD2091N; Entorno de Expacio Mérida · Catastro INSPIRE, PNOA y levantamiento Berrio; Levantamiento Berrio · parcelas I-27 Vial 3 e I-18 Vial 4; IGN · ortofotografía PNOA de máxima actualidad; Indicación del cliente · entorno de 200 m con aparcamientos y luminarias ilustrativos; Group: BIM · Entorno · parcelas catastrales
JH_InformacionBIM - buildingId: context; buildingName: Entorno exterior de la parcela; level: Exterior · contexto de 200 m; category: Parcela catastral próxima · 9716701QD2091N; ifcClass: IfcGeographicElement; status: derivado; source: {"documentId":"SDGC-CP-9716701QD2091N","title":"Dirección General del Catastro · parcela 9716701QD2091N","date":"2026-09-09","url":"https://www.catastro.hacienda.gob.es/webinspire/index.html","note":"Geometría del servicio vigente consultado el 09/09/2026. La fecha de alta del registro no es una fecha de levantamiento. Contexto recortado a 200 m; no identifica la nueva parcela I-18N."}; material: {"name":"Parcela exterior · suelo de referencia","status":"provisional","source":"Acabado visual aproximado; no especificación de proyecto."}; appearance: {"profileId":"ctx_plot_1","name":"Parcela exterior · suelo de referencia","status":"criterio_visual","basis":"Acabado de contexto orientativo, sin especificación de obra."}; dimensions: {"documented":[],"assumed":[{"label":"Cota exterior","value":"Plano simplificado ajustado a puntos de acera; extrapolación orientativa","unit":""}],"geometry":[{"label":"Extensión representada X","value":45.0616,"unit":"m"},{"label":"Extensión representada Y","value":119.8104,"unit":"m"},{"label":"Extensión representada Z","value":0.7043,"unit":"m"}]}; classification: {"layerId":"context_parcels","layerName":"Entorno · parcelas catastrales","function":"Parcela catastral próxima · 9716701QD2091N"}; visualLayer: {"id":"context_parcels","name":"Entorno · parcelas catastrales","defaultVisible":false}; representationKind: contexto_cartografico_derivado; quantityEligible: no; positioning: {"Sistema":"ETRS89 / UTM 29N · metros","Origen del modelo":"X 729400 · Y 4301550 · Z 285 m","Alcance":"Hasta 200 m desde el lindero del proyecto; solo exterior de parcela","Planta":"Catastro vigente consultado, contraste con ortofoto PNOA y levantamiento de aceras","Altimetría":"Plano ajustado a 213 puntos XYZ de aceras, extrapolado al resto del contexto; no es un MDT levantado"}; issues: ["Contexto para lectura del emplazamiento; planta derivada de cartografía, cotas y detalles simplificados. No para construcción ni mediciones de obra.","Las mediciones en el entorno expresan la geometría representada y conservan la precisión de su fuente."]; cadastralReference: 9716701QD2091N; cadastralRecordBeginLifespan: 2018-01-15T00:00:00; geometryMetrics: {"boundingBoxM":{"min":[292.18,65.678649,3.801962],"max":[337.241628,185.489016,4.506291]},"extentsM":[45.061628,119.810367,0.704329],"meshSurfaceM2":7840.45931,"meshVolumeM3":312.677426,"closedSolid":true,"basis":"Entorno de coordinación: trazados derivados de las fuentes indicadas por elemento; cotas, espesores, acabados y mobiliario orientativos cuando no están documentados. No acredita propiedad, servidumbres ni cantidades de obra y no es una base de construcción."}
JH_Trazabilidad - Origen: Dirección General del Catastro · parcela 9716701QD2091N; Estado: derivado; Capa BIM: Entorno · parcelas catastrales; Mediciones de obra: Excluido; Identificador: CTX-PARCEL-9716701QD2091N; Categoria: Parcela catastral próxima · 9716701QD2091N; ClaseIFC: IfcGeographicElement; EstadoDeInformacion: derivado; DocumentoFuente: {"documentId":"SDGC-CP-9716701QD2091N","title":"Dirección General del Catastro · parcela 9716701QD2091N","date":"2026-09-09","url":"https://www.catastro.hacienda.gob.es/webinspire/index.html","note":"Geometría del servicio vigente consultado el 09/09/2026. La fecha de alta del registro no es una fecha de levantamiento. Contexto recortado a 200 m; no identifica la nueva parcela I-18N."}; IncidenciasPendientes: ["Contexto para lectura del emplazamiento; planta derivada de cartografía, cotas y detalles simplificados. No para construcción ni mediciones de obra.","Las mediciones en el entorno expresan la geometría representada y conservan la precisión de su fuente."]; UsoDeLasMagnitudes: Entorno de coordinación: trazados derivados de las fuentes indicadas por elemento; cotas, espesores, acabados y mobiliario orientativos cuando no están documentados. No acredita propiedad, servidumbres ni cantidades de obra y no es una base de construcción.
JH_CriterioDePosicion - PosicionYEstado: {"Sistema":"ETRS89 / UTM 29N · metros","Origen del modelo":"X 729400 · Y 4301550 · Z 285 m","Alcance":"Hasta 200 m desde el lindero del proyecto; solo exterior de parcela","Planta":"Catastro vigente consultado, contraste con ortofoto PNOA y levantamiento de aceras","Altimetría":"Plano ajustado a 213 puntos XYZ de aceras, extrapolado al resto del contexto; no es un MDT levantado"}
JH_EvidenciaDeMaterial - name: Parcela exterior · suelo de referencia; status: provisional; source: Acabado visual aproximado; no especificación de proyecto.
JH_CapaBIM - IdentificadorCapa: context_parcels; NombreCapa: Entorno · parcelas catastrales; Funcion: Parcela catastral próxima · 9716701QD2091N; VisibilidadInicial: no
JH_EntornoContexto - Estado: derivado; Origen: {"documentId":"SDGC-CP-9716701QD2091N","title":"Dirección General del Catastro · parcela 9716701QD2091N","date":"2026-09-09","url":"https://www.catastro.hacienda.gob.es/webinspire/index.html","note":"Geometría del servicio vigente consultado el 09/09/2026. La fecha de alta del registro no es una fecha de levantamiento. Contexto recortado a 200 m; no identifica la nueva parcela I-18N."}; Posicion: {"Sistema":"ETRS89 / UTM 29N · metros","Origen del modelo":"X 729400 · Y 4301550 · Z 285 m","Alcance":"Hasta 200 m desde el lindero del proyecto; solo exterior de parcela","Planta":"Catastro vigente consultado, contraste con ortofoto PNOA y levantamiento de aceras","Altimetría":"Plano ajustado a 213 puntos XYZ de aceras, extrapolado al resto del contexto; no es un MDT levantado"}; DimensionesSupuestas: [{"label":"Cota exterior","value":"Plano simplificado ajustado a puntos de acera; extrapolación orientativa","unit":""}]; IncluirEnMediciones: no; EsquemaIlustrativo: no; Criterio: Entorno de coordinación: trazados derivados de las fuentes indicadas por elemento; cotas, espesores, acabados y mobiliario orientativos cuando no están documentados. No acredita propiedad, servidumbres ni cantidades de obra y no es una base de construcción.

# IfcGeographicElement: Parcela catastral próxima · 9716703QD2091N
In: Parcela industrial Jinhong
Description: Entorno de coordinación: trazados derivados de las fuentes indicadas por elemento; cotas, espesores, acabados y mobiliario orientativos cuando no están documentados. No acredita propiedad, servidumbres ni cantidades de obra y no es una base de construcción.; PredefinedType: USERDEFINED; Document: Dirección General del Catastro · parcela 9716703QD2091N; Entorno de Expacio Mérida · Catastro INSPIRE, PNOA y levantamiento Berrio; Levantamiento Berrio · parcelas I-27 Vial 3 e I-18 Vial 4; IGN · ortofotografía PNOA de máxima actualidad; Indicación del cliente · entorno de 200 m con aparcamientos y luminarias ilustrativos; Group: BIM · Entorno · parcelas catastrales
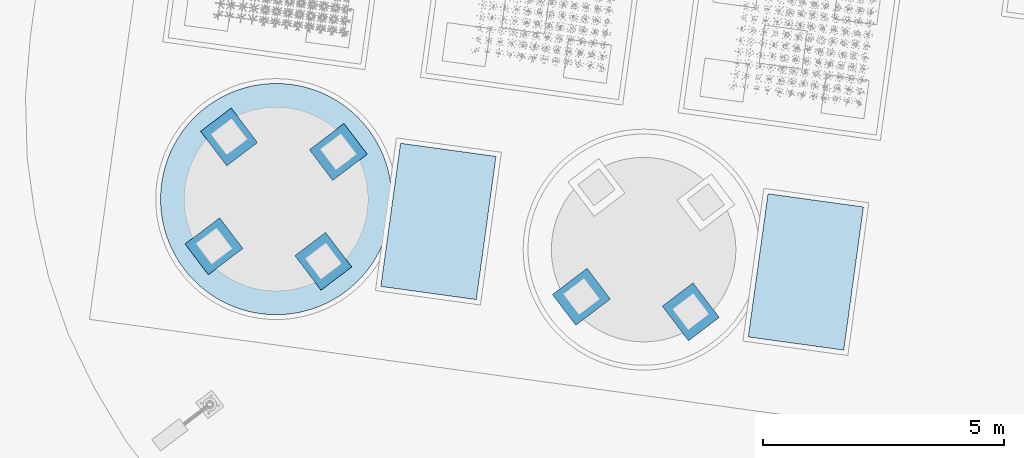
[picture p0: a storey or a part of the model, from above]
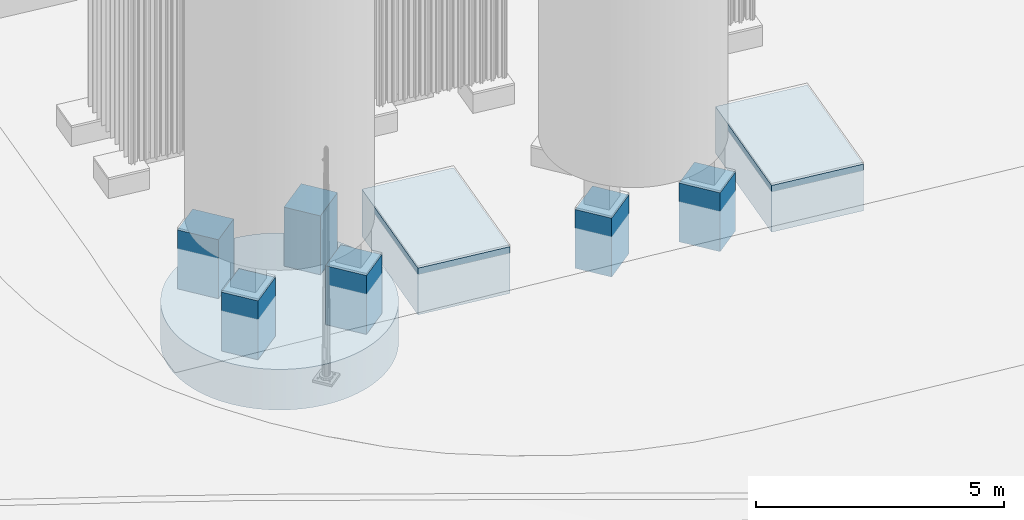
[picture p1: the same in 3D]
Properties of the parts of a building model (IFC4), part 87 of 134

# IfcGeographicElement: Parcela catastral próxima · 9716703QD2091N
JH_InformacionBIM - buildingId: context; buildingName: Entorno exterior de la parcela; level: Exterior · contexto de 200 m; category: Parcela catastral próxima · 9716703QD2091N; ifcClass: IfcGeographicElement; status: derivado; source: {"documentId":"SDGC-CP-9716703QD2091N","title":"Dirección General del Catastro · parcela 9716703QD2091N","date":"2026-09-09","url":"https://www.catastro.hacienda.gob.es/webinspire/index.html","note":"Geometría del servicio vigente consultado el 09/09/2026. La fecha de alta del registro no es una fecha de levantamiento. Contexto recortado a 200 m; no identifica la nueva parcela I-18N."}; material: {"name":"Parcela exterior · suelo de referencia","status":"provisional","source":"Acabado visual aproximado; no especificación de proyecto."}; appearance: {"profileId":"ctx_plot_2","name":"Parcela exterior · suelo de referencia","status":"criterio_visual","basis":"Acabado de contexto orientativo, sin especificación de obra."}; dimensions: {"documented":[],"assumed":[{"label":"Cota exterior","value":"Plano simplificado ajustado a puntos de acera; extrapolación orientativa","unit":""}],"geometry":[{"label":"Extensión representada X","value":49.6904,"unit":"m"},{"label":"Extensión representada Y","value":93.2937,"unit":"m"},{"label":"Extensión representada Z","value":0.8346,"unit":"m"}]}; classification: {"layerId":"context_parcels","layerName":"Entorno · parcelas catastrales","function":"Parcela catastral próxima · 9716703QD2091N"}; visualLayer: {"id":"context_parcels","name":"Entorno · parcelas catastrales","defaultVisible":false}; representationKind: contexto_cartografico_derivado; quantityEligible: no; positioning: {"Sistema":"ETRS89 / UTM 29N · metros","Origen del modelo":"X 729400 · Y 4301550 · Z 285 m","Alcance":"Hasta 200 m desde el lindero del proyecto; solo exterior de parcela","Planta":"Catastro vigente consultado, contraste con ortofoto PNOA y levantamiento de aceras","Altimetría":"Plano ajustado a 213 puntos XYZ de aceras, extrapolado al resto del contexto; no es un MDT levantado"}; issues: ["Contexto para lectura del emplazamiento; planta derivada de cartografía, cotas y detalles simplificados. No para construcción ni mediciones de obra.","Las mediciones en el entorno expresan la geometría representada y conservan la precisión de su fuente."]; cadastralReference: 9716703QD2091N; cadastralRecordBeginLifespan: 2018-01-15T00:00:00; geometryMetrics: {"boundingBoxM":{"min":[285.94,-21.823669,3.526066],"max":[335.630392,71.47,4.360623]},"extentsM":[49.690392,93.293669,0.834557],"meshSurfaceM2":7271.347647,"meshVolumeM3":290.021187,"closedSolid":true,"basis":"Entorno de coordinación: trazados derivados de las fuentes indicadas por elemento; cotas, espesores, acabados y mobiliario orientativos cuando no están documentados. No acredita propiedad, servidumbres ni cantidades de obra y no es una base de construcción."}
JH_Trazabilidad - Origen: Dirección General del Catastro · parcela 9716703QD2091N; Estado: derivado; Capa BIM: Entorno · parcelas catastrales; Mediciones de obra: Excluido; Identificador: CTX-PARCEL-9716703QD2091N; Categoria: Parcela catastral próxima · 9716703QD2091N; ClaseIFC: IfcGeographicElement; EstadoDeInformacion: derivado; DocumentoFuente: {"documentId":"SDGC-CP-9716703QD2091N","title":"Dirección General del Catastro · parcela 9716703QD2091N","date":"2026-09-09","url":"https://www.catastro.hacienda.gob.es/webinspire/index.html","note":"Geometría del servicio vigente consultado el 09/09/2026. La fecha de alta del registro no es una fecha de levantamiento. Contexto recortado a 200 m; no identifica la nueva parcela I-18N."}; IncidenciasPendientes: ["Contexto para lectura del emplazamiento; planta derivada de cartografía, cotas y detalles simplificados. No para construcción ni mediciones de obra.","Las mediciones en el entorno expresan la geometría representada y conservan la precisión de su fuente."]; UsoDeLasMagnitudes: Entorno de coordinación: trazados derivados de las fuentes indicadas por elemento; cotas, espesores, acabados y mobiliario orientativos cuando no están documentados. No acredita propiedad, servidumbres ni cantidades de obra y no es una base de construcción.
JH_CriterioDePosicion - PosicionYEstado: {"Sistema":"ETRS89 / UTM 29N · metros","Origen del modelo":"X 729400 · Y 4301550 · Z 285 m","Alcance":"Hasta 200 m desde el lindero del proyecto; solo exterior de parcela","Planta":"Catastro vigente consultado, contraste con ortofoto PNOA y levantamiento de aceras","Altimetría":"Plano ajustado a 213 puntos XYZ de aceras, extrapolado al resto del contexto; no es un MDT levantado"}
JH_EvidenciaDeMaterial - name: Parcela exterior · suelo de referencia; status: provisional; source: Acabado visual aproximado; no especificación de proyecto.
JH_CapaBIM - IdentificadorCapa: context_parcels; NombreCapa: Entorno · parcelas catastrales; Funcion: Parcela catastral próxima · 9716703QD2091N; VisibilidadInicial: no
JH_EntornoContexto - Estado: derivado; Origen: {"documentId":"SDGC-CP-9716703QD2091N","title":"Dirección General del Catastro · parcela 9716703QD2091N","date":"2026-09-09","url":"https://www.catastro.hacienda.gob.es/webinspire/index.html","note":"Geometría del servicio vigente consultado el 09/09/2026. La fecha de alta del registro no es una fecha de levantamiento. Contexto recortado a 200 m; no identifica la nueva parcela I-18N."}; Posicion: {"Sistema":"ETRS89 / UTM 29N · metros","Origen del modelo":"X 729400 · Y 4301550 · Z 285 m","Alcance":"Hasta 200 m desde el lindero del proyecto; solo exterior de parcela","Planta":"Catastro vigente consultado, contraste con ortofoto PNOA y levantamiento de aceras","Altimetría":"Plano ajustado a 213 puntos XYZ de aceras, extrapolado al resto del contexto; no es un MDT levantado"}; DimensionesSupuestas: [{"label":"Cota exterior","value":"Plano simplificado ajustado a puntos de acera; extrapolación orientativa","unit":""}]; IncluirEnMediciones: no; EsquemaIlustrativo: no; Criterio: Entorno de coordinación: trazados derivados de las fuentes indicadas por elemento; cotas, espesores, acabados y mobiliario orientativos cuando no están documentados. No acredita propiedad, servidumbres ni cantidades de obra y no es una base de construcción.

# IfcGeographicElement: Suelo exterior · referencia provisional
In: Parcela industrial Jinhong
Description: Cruce subterráneo provisional solicitado por el cliente. Salida al otro lado de la plataforma viaria; cotas, profundidad, soportes y conexión final pendientes del plano definitivo. No para construcción ni cantidades de obra.; PredefinedType: USERDEFINED; Document: Indicación del cliente y croquis sobre el visor · 08/09/2026; Corrección del cliente · cruce subterráneo completo del vial exterior; Group: BIM · Nitrógeno · tramo enterrado
JH_CapaBIM - IdentificadorCapa: pipe_underground; NombreCapa: Nitrógeno · tramo enterrado; Funcion: Suelo exterior · referencia provisional; VisibilidadInicial: yes
JH_EsquemaProvisional - Estado: No para construcción; Origen: {"documentId":"JH-USER-CROSSING-20260909","title":"Corrección del cliente · cruce subterráneo completo del vial exterior","date":"2026-09-09","sheet":"Croquis rojo sobre el visor con entorno","note":"Entrar al subsuelo dentro de la parcela, atravesar calzada y aceras, y salir al otro lado. Geometría provisional de coordinación; diámetros aproximados 0,50 y 0,20 m."}; DimensionesSupuestas: [{"label":"Ancho del contexto provisional","value":4.8,"unit":"m"},{"label":"Espesor gráfico","value":0.12,"unit":"m"}]; Posicion: {"Recorrido":"Bajante dentro de la parcela, cruce de toda la calzada y ambas aceras, subida en el margen opuesto.","Salida":"Eje situado aproximadamente 3 m después del borde exterior de la acera opuesta.","Cotas":"Superficie de contexto simplificada; profundidad de visualización, no cálculo de diseño.","Dimensiones":"Diámetros y radios provisionales; conservar hasta recibir plano."}; IncluirEnMediciones: no; Criterio: {"enabled":true,"basis":"Cruce subterráneo provisional solicitado por el cliente. Salida al otro lado de la plataforma viaria; cotas, profundidad, soportes y conexión final pendientes del plano definitivo. No para construcción ni cantidades de obra.","pending":["Plano definitivo de cruce","Profundidad y servicios enterrados","Protección y apoyos","Destino y conexión"]}
JH_InformacionBIM - buildingId: site; buildingName: Urbanización y parcela; level: Exterior · esquema de servicios; category: Suelo exterior · referencia provisional; ifcClass: IfcGeographicElement; status: provisional; source: {"documentId":"JH-USER-CROSSING-20260909","title":"Corrección del cliente · cruce subterráneo completo del vial exterior","date":"2026-09-09","sheet":"Croquis rojo sobre el visor con entorno","note":"Entrar al subsuelo dentro de la parcela, atravesar calzada y aceras, y salir al otro lado. Geometría provisional de coordinación; diámetros aproximados 0,50 y 0,20 m."}; material: {"name":"Suelo exterior de referencia","status":"provisional","source":"Material, espesor, aislamiento y protección pendientes de ingeniería."}; dimensions: {"documented":[],"assumed":[{"label":"Ancho del contexto provisional","value":4.8,"unit":"m"},{"label":"Espesor gráfico","value":0.12,"unit":"m"}],"geometry":[{"label":"Extensión representada X","value":8.882633,"unit":"m"},{"label":"Extensión representada Y","value":30.674226,"unit":"m"},{"label":"Extensión representada Z","value":0.299371,"unit":"m"}]}; appearance: {"profileId":"n2_external_ground","name":"Suelo exterior de referencia","status":"criterio_visual","basis":"Color y acabado orientativos para distinguir el esquema solicitado; material sin especificación confirmada."}; classification: {"layerId":"pipe_underground","layerName":"Nitrógeno · tramo enterrado","function":"Suelo exterior · referencia provisional"}; visualLayer: {"id":"pipe_underground","name":"Nitrógeno · tramo enterrado","defaultVisible":true}; representationKind: superficie_de_contexto_provisional; conceptual: {"enabled":true,"basis":"Cruce subterráneo provisional solicitado por el cliente. Salida al otro lado de la plataforma viaria; cotas, profundidad, soportes y conexión final pendientes del plano definitivo. No para construcción ni cantidades de obra.","pending":["Plano definitivo de cruce","Profundidad y servicios enterrados","Protección y apoyos","Destino y conexión"]}; positioning: {"Recorrido":"Bajante dentro de la parcela, cruce de toda la calzada y ambas aceras, subida en el margen opuesto.","Salida":"Eje situado aproximadamente 3 m después del borde exterior de la acera opuesta.","Cotas":"Superficie de contexto simplificada; profundidad de visualización, no cálculo de diseño.","Dimensiones":"Diámetros y radios provisionales; conservar hasta recibir plano."}; quantityEligible: no; issues: ["Cruce subterráneo provisional solicitado por el cliente. Salida al otro lado de la plataforma viaria; cotas, profundidad, soportes y conexión final pendientes del plano definitivo. No para construcción ni cantidades de obra."]; isDisplayGround: yes; isUnderground: no; geometryMetrics: {"boundingBoxM":{"min":[48.608301,-18.117308,0.754793],"max":[57.490934,12.556918,1.054164]},"extentsM":[8.882633,30.674226,0.299371],"meshSurfaceM2":299.351839,"meshVolumeM3":17.454439,"closedSolid":true,"basis":"Cruce subterráneo provisional solicitado por el cliente. Salida al otro lado de la plataforma viaria; cotas, profundidad, soportes y conexión final pendientes del plano definitivo. No para construcción ni cantidades de obra."}
JH_Trazabilidad - Origen: Corrección del cliente · cruce subterráneo completo del vial exterior; Estado: Provisional · no para construcción; Capa BIM: Nitrógeno · tramo enterrado; Mediciones de obra: Excluido; Identificador: N2-EXTERNAL-GROUND; Categoria: Suelo exterior · referencia provisional; ClaseIFC: IfcGeographicElement; EstadoDeInformacion: provisional; DocumentoFuente: {"documentId":"JH-USER-CROSSING-20260909","title":"Corrección del cliente · cruce subterráneo completo del vial exterior","date":"2026-09-09","sheet":"Croquis rojo sobre el visor con entorno","note":"Entrar al subsuelo dentro de la parcela, atravesar calzada y aceras, y salir al otro lado. Geometría provisional de coordinación; diámetros aproximados 0,50 y 0,20 m."}; IncidenciasPendientes: ["Cruce subterráneo provisional solicitado por el cliente. Salida al otro lado de la plataforma viaria; cotas, profundidad, soportes y conexión final pendientes del plano definitivo. No para construcción ni cantidades de obra."]; UsoDeLasMagnitudes: Cruce subterráneo provisional solicitado por el cliente. Salida al otro lado de la plataforma viaria; cotas, profundidad, soportes y conexión final pendientes del plano definitivo. No para construcción ni cantidades de obra.
JH_CriterioDePosicion - PosicionYEstado: {"Recorrido":"Bajante dentro de la parcela, cruce de toda la calzada y ambas aceras, subida en el margen opuesto.","Salida":"Eje situado aproximadamente 3 m después del borde exterior de la acera opuesta.","Cotas":"Superficie de contexto simplificada; profundidad de visualización, no cálculo de diseño.","Dimensiones":"Diámetros y radios provisionales; conservar hasta recibir plano."}
JH_EvidenciaDeMaterial - name: Suelo exterior de referencia; status: provisional; source: Material, espesor, aislamiento y protección pendientes de ingeniería.

# IfcGeographicElement: Terreno exterior · alcance 200 m
In: Parcela industrial Jinhong
Description: Entorno de coordinación: trazados derivados de las fuentes indicadas por elemento; cotas, espesores, acabados y mobiliario orientativos cuando no están documentados. No acredita propiedad, servidumbres ni cantidades de obra y no es una base de construcción.; PredefinedType: USERDEFINED; Document: Entorno de Expacio Mérida · Catastro INSPIRE, PNOA y levantamiento Berrio; Levantamiento Berrio · parcelas I-27 Vial 3 e I-18 Vial 4; IGN · ortofotografía PNOA de máxima actualidad; Indicación del cliente · entorno de 200 m con aparcamientos y luminarias ilustrativos; Group: BIM · Entorno · superficie exterior
JH_InformacionBIM - buildingId: context; buildingName: Entorno exterior de la parcela; level: Exterior · contexto de 200 m; category: Terreno exterior · alcance 200 m; ifcClass: IfcGeographicElement; status: derivado; source: {"documentId":"JH-CONTEXT-GIS-20260909","title":"Entorno de Expacio Mérida · Catastro INSPIRE, PNOA y levantamiento Berrio","date":"2026-09-09","url":"https://www.catastro.hacienda.gob.es/webinspire/index.html","note":"Consulta cartográfica 09/09/2026. Linderos catastrales consultados en el servicio vigente; viales contrastados con PNOA y bordes levantados del paquete topográfico recibido el 28/07/2026. La fecha de consulta no es la fecha de vuelo. Se conserva el lindero del proyecto del 31/07/2026."}; material: {"name":"Terreno exterior de contexto","status":"provisional","source":"Acabado visual aproximado; no especificación de proyecto."}; appearance: {"profileId":"ctx_ground","name":"Terreno exterior de contexto","status":"criterio_visual","basis":"Acabado de contexto orientativo, sin especificación de obra."}; dimensions: {"documented":[],"assumed":[{"label":"Cota exterior","value":"Plano simplificado ajustado a puntos de acera; extrapolación orientativa","unit":""}],"geometry":[{"label":"Extensión representada X","value":543.3423,"unit":"m"},{"label":"Extensión representada Y","value":506.6832,"unit":"m"},{"label":"Extensión representada Z","value":6.7575,"unit":"m"}]}; classification: {"layerId":"context_ground","layerName":"Entorno · superficie exterior","function":"Terreno exterior · alcance 200 m"}; visualLayer: {"id":"context_ground","name":"Entorno · superficie exterior","defaultVisible":false}; representationKind: contexto_cartografico_derivado; quantityEligible: no; positioning: {"Sistema":"ETRS89 / UTM 29N · metros","Origen del modelo":"X 729400 · Y 4301550 · Z 285 m","Alcance":"Hasta 200 m desde el lindero del proyecto; solo exterior de parcela","Planta":"Catastro vigente consultado, contraste con ortofoto PNOA y levantamiento de aceras","Altimetría":"Plano ajustado a 213 puntos XYZ de aceras, extrapolado al resto del contexto; no es un MDT levantado"}; issues: ["Contexto para lectura del emplazamiento; planta derivada de cartografía, cotas y detalles simplificados. No para construcción ni mediciones de obra.","Las mediciones en el entorno expresan la geometría representada y conservan la precisión de su fuente."]; geometryMetrics: {"boundingBoxM":{"min":[-206.100721,-197.331588,-2.331247],"max":[337.241628,309.351583,4.426291]},"extentsM":[543.342349,506.683171,6.757538],"meshSurfaceM2":429205.51771,"meshVolumeM3":64279.999504,"closedSolid":true,"basis":"Entorno de coordinación: trazados derivados de las fuentes indicadas por elemento; cotas, espesores, acabados y mobiliario orientativos cuando no están documentados. No acredita propiedad, servidumbres ni cantidades de obra y no es una base de construcción."}
JH_Trazabilidad - Origen: Entorno de Expacio Mérida · Catastro INSPIRE, PNOA y levantamiento Berrio; Estado: derivado; Capa BIM: Entorno · superficie exterior; Mediciones de obra: Excluido; Identificador: CTX-GROUND; Categoria: Terreno exterior · alcance 200 m; ClaseIFC: IfcGeographicElement; EstadoDeInformacion: derivado; DocumentoFuente: {"documentId":"JH-CONTEXT-GIS-20260909","title":"Entorno de Expacio Mérida · Catastro INSPIRE, PNOA y levantamiento Berrio","date":"2026-09-09","url":"https://www.catastro.hacienda.gob.es/webinspire/index.html","note":"Consulta cartográfica 09/09/2026. Linderos catastrales consultados en el servicio vigente; viales contrastados con PNOA y bordes levantados del paquete topográfico recibido el 28/07/2026. La fecha de consulta no es la fecha de vuelo. Se conserva el lindero del proyecto del 31/07/2026."}; IncidenciasPendientes: ["Contexto para lectura del emplazamiento; planta derivada de cartografía, cotas y detalles simplificados. No para construcción ni mediciones de obra.","Las mediciones en el entorno expresan la geometría representada y conservan la precisión de su fuente."]; UsoDeLasMagnitudes: Entorno de coordinación: trazados derivados de las fuentes indicadas por elemento; cotas, espesores, acabados y mobiliario orientativos cuando no están documentados. No acredita propiedad, servidumbres ni cantidades de obra y no es una base de construcción.
JH_CriterioDePosicion - PosicionYEstado: {"Sistema":"ETRS89 / UTM 29N · metros","Origen del modelo":"X 729400 · Y 4301550 · Z 285 m","Alcance":"Hasta 200 m desde el lindero del proyecto; solo exterior de parcela","Planta":"Catastro vigente consultado, contraste con ortofoto PNOA y levantamiento de aceras","Altimetría":"Plano ajustado a 213 puntos XYZ de aceras, extrapolado al resto del contexto; no es un MDT levantado"}
JH_EvidenciaDeMaterial - name: Terreno exterior de contexto; status: provisional; source: Acabado visual aproximado; no especificación de proyecto.
JH_CapaBIM - IdentificadorCapa: context_ground; NombreCapa: Entorno · superficie exterior; Funcion: Terreno exterior · alcance 200 m; VisibilidadInicial: no
JH_EntornoContexto - Estado: derivado; Origen: {"documentId":"JH-CONTEXT-GIS-20260909","title":"Entorno de Expacio Mérida · Catastro INSPIRE, PNOA y levantamiento Berrio","date":"2026-09-09","url":"https://www.catastro.hacienda.gob.es/webinspire/index.html","note":"Consulta cartográfica 09/09/2026. Linderos catastrales consultados en el servicio vigente; viales contrastados con PNOA y bordes levantados del paquete topográfico recibido el 28/07/2026. La fecha de consulta no es la fecha de vuelo. Se conserva el lindero del proyecto del 31/07/2026."}; Posicion: {"Sistema":"ETRS89 / UTM 29N · metros","Origen del modelo":"X 729400 · Y 4301550 · Z 285 m","Alcance":"Hasta 200 m desde el lindero del proyecto; solo exterior de parcela","Planta":"Catastro vigente consultado, contraste con ortofoto PNOA y levantamiento de aceras","Altimetría":"Plano ajustado a 213 puntos XYZ de aceras, extrapolado al resto del contexto; no es un MDT levantado"}; DimensionesSupuestas: [{"label":"Cota exterior","value":"Plano simplificado ajustado a puntos de acera; extrapolación orientativa","unit":""}]; IncluirEnMediciones: no; EsquemaIlustrativo: no; Criterio: Entorno de coordinación: trazados derivados de las fuentes indicadas por elemento; cotas, espesores, acabados y mobiliario orientativos cuando no están documentados. No acredita propiedad, servidumbres ni cantidades de obra y no es una base de construcción.

# IfcGeographicElement: Viales exteriores · red existente de referencia
In: Parcela industrial Jinhong
Description: Cruce subterráneo provisional solicitado por el cliente. Salida al otro lado de la plataforma viaria; cotas, profundidad, soportes y conexión final pendientes del plano definitivo. No para construcción ni cantidades de obra.; PredefinedType: USERDEFINED; Document: Entorno de Expacio Mérida · Catastro INSPIRE, PNOA y levantamiento Berrio; Levantamiento Berrio · parcelas I-27 Vial 3 e I-18 Vial 4; IGN · ortofotografía PNOA de máxima actualidad; Indicación del cliente · entorno de 200 m con aparcamientos y luminarias ilustrativos; Corrección del cliente · cruce subterráneo completo del vial exterior; Group: BIM · Entorno · viales y aceras
JH_CapaBIM - IdentificadorCapa: context_roads; NombreCapa: Entorno · viales y aceras; Funcion: Viales exteriores · red existente de referencia; VisibilidadInicial: no
JH_EntornoContexto - Estado: derivado; Origen: {"documentId":"JH-CONTEXT-GIS-20260909","title":"Entorno de Expacio Mérida · Catastro INSPIRE, PNOA y levantamiento Berrio","date":"2026-09-09","url":"https://www.catastro.hacienda.gob.es/webinspire/index.html","note":"Consulta cartográfica 09/09/2026. Linderos catastrales consultados en el servicio vigente; viales contrastados con PNOA y bordes levantados del paquete topográfico recibido el 28/07/2026. La fecha de consulta no es la fecha de vuelo. Se conserva el lindero del proyecto del 31/07/2026."}; Posicion: {"Sistema":"ETRS89 / UTM 29N · metros","Origen del modelo":"X 729400 · Y 4301550 · Z 285 m","Alcance":"Hasta 200 m desde el lindero del proyecto; solo exterior de parcela","Planta":"Catastro vigente consultado, contraste con ortofoto PNOA y levantamiento de aceras","Altimetría":"Plano ajustado a 213 puntos XYZ de aceras, extrapolado al resto del contexto; no es un MDT levantado"}; DimensionesSupuestas: [{"label":"Cota exterior","value":"Plano simplificado ajustado a puntos de acera; extrapolación orientativa","unit":""}]; IncluirEnMediciones: no; EsquemaIlustrativo: no; Criterio: Entorno de coordinación: trazados derivados de las fuentes indicadas por elemento; cotas, espesores, acabados y mobiliario orientativos cuando no están documentados. No acredita propiedad, servidumbres ni cantidades de obra y no es una base de construcción.
JH_InformacionBIM - buildingId: context; buildingName: Entorno exterior de la parcela; level: Exterior · contexto de 200 m; category: Viales exteriores · red existente de referencia; ifcClass: IfcGeographicElement; status: derivado; source: {"documentId":"JH-CONTEXT-GIS-20260909","title":"Entorno de Expacio Mérida · Catastro INSPIRE, PNOA y levantamiento Berrio","date":"2026-09-09","url":"https://www.catastro.hacienda.gob.es/webinspire/index.html","note":"Consulta cartográfica 09/09/2026. Linderos catastrales consultados en el servicio vigente; viales contrastados con PNOA y bordes levantados del paquete topográfico recibido el 28/07/2026. La fecha de consulta no es la fecha de vuelo. Se conserva el lindero del proyecto del 31/07/2026."}; material: {"name":"Calzada exterior · asfalto","status":"provisional","source":"Acabado visual aproximado; no especificación de proyecto."}; appearance: {"profileId":"ctx_road","name":"Calzada exterior · asfalto","status":"criterio_visual","basis":"Acabado de contexto orientativo, sin especificación de obra."}; dimensions: {"documented":[],"assumed":[{"label":"Cota exterior","value":"Plano simplificado ajustado a puntos de acera; extrapolación orientativa","unit":""}],"geometry":[{"label":"Extensión representada X","value":529.4187,"unit":"m"},{"label":"Extensión representada Y","value":482.8864,"unit":"m"},{"label":"Extensión representada Z","value":6.0652,"unit":"m"}]}; classification: {"layerId":"context_roads","layerName":"Entorno · viales y aceras","function":"Viales exteriores · red existente de referencia"}; visualLayer: {"id":"context_roads","name":"Entorno · viales y aceras","defaultVisible":false}; representationKind: contexto_cartografico_derivado; quantityEligible: no; positioning: {"Sistema":"ETRS89 / UTM 29N · metros","Origen del modelo":"X 729400 · Y 4301550 · Z 285 m","Alcance":"Hasta 200 m desde el lindero del proyecto; solo exterior de parcela","Planta":"Catastro vigente consultado, contraste con ortofoto PNOA y levantamiento de aceras","Altimetría":"Plano ajustado a 213 puntos XYZ de aceras, extrapolado al resto del contexto; no es un MDT levantado"}; issues: ["Contexto para lectura del emplazamiento; planta derivada de cartografía, cotas y detalles simplificados. No para construcción ni mediciones de obra.","Las mediciones en el entorno expresan la geometría representada y conservan la precisión de su fuente.","Cruce provisional corregido: la salida de nitrógeno se sitúa al otro lado de calzada y aceras; ubicación y rasante final pendientes de ingeniería."]; roadBasis: Envolvente viaria catastral seleccionada por ortofoto; aceras simplificadas a 2,35 m y planta contrastada con el levantamiento. No se asignan nombres de calle sin correspondencia confirmada.; geometryMetrics: {"boundingBoxM":{"min":[-206.095411,-197.05778,-2.034318],"max":[323.323301,285.828594,4.030845]},"extentsM":[529.418712,482.886374,6.065163],"meshSurfaceM2":49967.446548,"meshVolumeM3":4429.652979,"closedSolid":true,"basis":"Entorno de coordinación: trazados derivados de las fuentes indicadas por elemento; cotas, espesores, acabados y mobiliario orientativos cuando no están documentados. No acredita propiedad, servidumbres ni cantidades de obra y no es una base de construcción."}
JH_Trazabilidad - Origen: Entorno de Expacio Mérida · Catastro INSPIRE, PNOA y levantamiento Berrio; Estado: derivado; Capa BIM: Entorno · viales y aceras; Mediciones de obra: Excluido; Identificador: CTX-ROAD-NETWORK; Categoria: Viales exteriores · red existente de referencia; ClaseIFC: IfcGeographicElement; EstadoDeInformacion: derivado; DocumentoFuente: {"documentId":"JH-CONTEXT-GIS-20260909","title":"Entorno de Expacio Mérida · Catastro INSPIRE, PNOA y levantamiento Berrio","date":"2026-09-09","url":"https://www.catastro.hacienda.gob.es/webinspire/index.html","note":"Consulta cartográfica 09/09/2026. Linderos catastrales consultados en el servicio vigente; viales contrastados con PNOA y bordes levantados del paquete topográfico recibido el 28/07/2026. La fecha de consulta no es la fecha de vuelo. Se conserva el lindero del proyecto del 31/07/2026."}; IncidenciasPendientes: ["Contexto para lectura del emplazamiento; planta derivada de cartografía, cotas y detalles simplificados. No para construcción ni mediciones de obra.","Las mediciones en el entorno expresan la geometría representada y conservan la precisión de su fuente.","Cruce provisional corregido: la salida de nitrógeno se sitúa al otro lado de calzada y aceras; ubicación y rasante final pendientes de ingeniería."]; UsoDeLasMagnitudes: Cruce subterráneo provisional solicitado por el cliente. Salida al otro lado de la plataforma viaria; cotas, profundidad, soportes y conexión final pendientes del plano definitivo. No para construcción ni cantidades de obra.
JH_CriterioDePosicion - PosicionYEstado: {"Sistema":"ETRS89 / UTM 29N · metros","Origen del modelo":"X 729400 · Y 4301550 · Z 285 m","Alcance":"Hasta 200 m desde el lindero del proyecto; solo exterior de parcela","Planta":"Catastro vigente consultado, contraste con ortofoto PNOA y levantamiento de aceras","Altimetría":"Plano ajustado a 213 puntos XYZ de aceras, extrapolado al resto del contexto; no es un MDT levantado"}
JH_EvidenciaDeMaterial - name: Calzada exterior · asfalto; status: provisional; source: Acabado visual aproximado; no especificación de proyecto.

# IfcGeographicElement: Zonas verdes (2)
In: Parcela industrial Jinhong
Description: Zonas verdes; PredefinedType: USERDEFINED; Document: Planos de urbanización y ordenación general de Jinhong; Group: Urbanización; BIM · Urbanización
JH_DimensionesDelModelo - Espesor de visualización adoptado: 0.1 m
JH_InformacionBIM - buildingId: site; buildingName: Urbanización y parcela; level: Exterior · rasantes de proyecto pendientes de coordinación; category: Zonas verdes; ifcClass: IfcGeographicElement; material: {"name":"No especificado","source":"Sin especificación de material en la documentación revisada","status":"unknown"}; source: {"documentId":"URB-20260731","title":"Planos de urbanización y ordenación general de Jinhong","sheet":"U004 · página 5","date":"2026-07-31"}; status: provisional; issues: ["Espesor supuesto exclusivamente para visualizar la superficie; material, composición y espesor constructivo sin especificar.","Cotas interpoladas a partir de puntos de proyecto del plano general. No sustituyen la rasante aprobada, los perfiles de viales ni el TIN de proyecto."]; ifcAssociations: {"material":false,"document":true,"quantities":true,"containerGuid":"17utmjd_LKsAVvPyuSUhFt","containerName":"Parcela industrial Jinhong"}; visualLayer: {"id":"site","name":"Urbanización"}; materialAppearance: {"profileId":"grass","name":"Zona verde","materialName":"No especificado","physicalMaterialStatus":"unknown","physicalMaterialSource":"Sin especificación de material en la documentación revisada","appearanceStatus":"provisional","appearanceBasis":"Uso de zona verde documentado; especie, plantación y sustrato sin definir.","note":"La apariencia gráfica no modifica ni confirma la especificación física del material."}; componentSeparation: {"status":"objeto_independiente","note":"Control de visibilidad del objeto completo; la clasificación no altera la malla."}; classification: {"layerId":"site","layerName":"Urbanización","role":"Zonas verdes","basis":"Clasificación por función del elemento; no modifica las especificaciones documentales."}; layerId: site; appearance: {"profileId":"grass","name":"Zona verde","status":"provisional","basis":"Uso de zona verde documentado; especie, plantación y sustrato sin definir.","physicalMaterialUnchanged":true}
JH_Trazabilidad - Documento de origen: Planos de urbanización y ordenación general de Jinhong · 2026-07-31 · U004 · página 5; Lámina de origen: U004 · página 5 del PDF; Geometría en planta: Triángulos de relleno originales del PDF, registrados mediante puntos de control UTM; contorno extraído de la documentación.; Estado de las cotas: Superficie de visualización obtenida por interpolación de las cotas de proyecto indicadas. No equivale a un perfil longitudinal aprobado ni al TIN original de proyecto.; Espesor de visualización (m): 0.1; Estado del espesor: Espesor supuesto exclusivamente para visualización; no utilizable en mediciones.; Estado del modelo: Coordinación preliminar; pendiente de revisión.; Disciplina: Urbanización; Clase IFC: IfcGeographicElement; Fase del modelo: V0.1 · Reconstrucción a partir de planos y coordinación preliminar; Representación geométrica IFC: Sólido IFC4 mediante malla triangular cerrada; Aplicabilidad a mediciones: Los equipos se representan mediante envolventes. Los espesores y alturas supuestos y el volumen de las envolventes no representan cantidades de materiales, compras, construcción o fabricación.; Material: No especificado; Estado de la información: provisional; Capa BIM: Urbanización; Acabado de visualización: Zona verde; Estado del acabado: provisional; Categoria: Zonas verdes; ClaseIFC: IfcGeographicElement; EstadoDeInformacion: provisional; DocumentoFuente: {"documentId":"URB-20260731","title":"Planos de urbanización y ordenación general de Jinhong","sheet":"U004 · página 5","date":"2026-07-31"}; IncidenciasPendientes: ["Espesor supuesto exclusivamente para visualizar la superficie; material, composición y espesor constructivo sin especificar.","Cotas interpoladas a partir de puntos de proyecto del plano general. No sustituyen la rasante aprobada, los perfiles de viales ni el TIN de proyecto."]; UsoDeLasMagnitudes: Geometría de coordinación. Los volúmenes de referencia y subcomponentes no son cantidades de material ni componentes de fabricación certificados.
JH_EvidenciaDeMaterial - name: No especificado; source: Sin especificación de material en la documentación revisada; status: unknown
JH_CapaBIM - IdentificadorCapa: site; NombreCapa: Urbanización; Funcion: Zonas verdes; VisibilidadInicial: yes
JH_AcabadoVisual - Perfil: grass; Acabado: Zona verde; ColorRGB: [0.482353,0.568627,0.388235]; Rugosidad: 1; Metallicidad: 0; Estado: provisional; Referencia: Uso de zona verde documentado; especie, plantación y sustrato sin definir.; Nota: La apariencia no certifica el material físico ni el acabado de fabricación.
Name | Extensión de la malla en X (m) = ExtensionX (m) | Extensión de la malla en Y (m) = ExtensionY (m) | Extensión de la malla en Z (m) = ExtensionZ (m) | Cota inferior del modelo (m) | Cota superior del modelo (m) | Superficie proyectada en planta extraída del PDF (m2) = Superficie proyectada en planta (m²) | SuperficieDeLaMalla (m2) | VolumenGeometrico (m3) | dimensions | positioning = PosicionYEstado | geometryMetrics | visualizationIdentity | Identificador del objeto = Identificador
Zona verde 01 | 95.5214 | 81.0794 | 1.90964 | 285.851 | 287.76 | 4834.86 | 9718.33 | 483.486 | {"documented":[],"geometry":[{"label":"Extensión de la malla en X","value":95.521382,"unit":"m","source":"Calculada a partir de los vértices del modelo","status":"derivado"},{"label":"Extensión de la malla en Y","value":81.079432,"unit":"m","source":"Calculada a partir de los vértices del modelo","status":"derivado"},{"label":"Extensión de la malla en Z","value":1.90964,"unit":"m","source":"Calculada a partir de los vértices del modelo","status":"derivado"},{"label":"Cota inferior del modelo","value":285.850825,"unit":"m","source":"Coordenada Z mínima de la malla más origen vertical de 285 m","status":"derivado"},{"label":"Cota superior del modelo","value":287.760465,"unit":"m","source":"Coordenada Z máxima de la malla más origen vertical de 285 m","status":"derivado"},{"label":"Superficie proyectada en planta extraída del PDF","value":4834.864,"unit":"m²","source":"URB-20260731 · U004 · triangulación del relleno","status":"derivado"},{"label":"Espesor de visualización adoptado","value":0.1,"unit":"m","source":"Convención de visualización del modelo","status":"provisional"}],"notes":["Las extensiones de la malla se miden en los ejes del proyecto tras el giro de implantación; no sustituyen las dimensiones locales del fabricante.","La envolvente, su volumen y los espesores de visualización no son volúmenes de material ni cantidades de compra, construcción o fabricación.","Las dimensiones documentadas distinguen cotas explícitas y medidas extraídas de contornos CAD; las dimensiones geométricas describen únicamente la malla publicada."]} | {"horizontalStatus":"derivado","verticalStatus":"provisional","baseElevationM":285.850825,"note":"Superficie de visualización obtenida por interpolación de las cotas de proyecto indicadas. No equivale a un perfil longitudinal aprobado ni al TIN original de proyecto."} | {"boundingBoxM":{"min":[31.172894,13.30766,0.850825],"max":[126.694276,94.387092,2.760465]},"extentsM":[95.521382,81.079432,1.90964],"meshSurfaceM2":9718.328547,"meshVolumeM3":483.486396,"closedSolid":true,"basis":"Geometría triangulada releída del IFC; envolventes y magnitudes no contractuales."} | {"elementId":"site_001","ifcGuid":"3LENz8aRzOqwLJkOo7IqQY","ifcClass":"IfcGeographicElement","buildingId":"site","buildingName":"Urbanización y parcela","sourceDocumentId":"URB-20260731","sourceRepresentationKind":"documentary_mesh"} | site_001
Zona verde 02 | 127.937 | 97.6513 | 1.62526 | 285.27 | 286.895 | 2001.68 | 4063.24 | 200.168 | {"documented":[],"geometry":[{"label":"Extensión de la malla en X","value":127.936594,"unit":"m","source":"Calculada a partir de los vértices del modelo","status":"derivado"},{"label":"Extensión de la malla en Y","value":97.651278,"unit":"m","source":"Calculada a partir de los vértices del modelo","status":"derivado"},{"label":"Extensión de la malla en Z","value":1.625264,"unit":"m","source":"Calculada a partir de los vértices del modelo","status":"derivado"},{"label":"Cota inferior del modelo","value":285.27,"unit":"m","source":"Coordenada Z mínima de la malla más origen vertical de 285 m","status":"derivado"},{"label":"Cota superior del modelo","value":286.895264,"unit":"m","source":"Coordenada Z máxima de la malla más origen vertical de 285 m","status":"derivado"},{"label":"Superficie proyectada en planta extraída del PDF","value":2001.68,"unit":"m²","source":"URB-20260731 · U004 · triangulación del relleno","status":"derivado"},{"label":"Espesor de visualización adoptado","value":0.1,"unit":"m","source":"Convención de visualización del modelo","status":"provisional"}],"notes":["Las extensiones de la malla se miden en los ejes del proyecto tras el giro de implantación; no sustituyen las dimensiones locales del fabricante.","La envolvente, su volumen y los espesores de visualización no son volúmenes de material ni cantidades de compra, construcción o fabricación.","Las dimensiones documentadas distinguen cotas explícitas y medidas extraídas de contornos CAD; las dimensiones geométricas describen únicamente la malla publicada."]} | {"horizontalStatus":"derivado","verticalStatus":"provisional","baseElevationM":285.27,"note":"Superficie de visualización obtenida por interpolación de las cotas de proyecto indicadas. No equivale a un perfil longitudinal aprobado ni al TIN original de proyecto."} | {"boundingBoxM":{"min":[-6.104322,3.276882,0.27],"max":[121.832272,100.92816,1.895264]},"extentsM":[127.936594,97.651278,1.625264],"meshSurfaceM2":4063.241891,"meshVolumeM3":200.167958,"closedSolid":true,"basis":"Geometría triangulada releída del IFC; envolventes y magnitudes no contractuales."} | {"elementId":"site_002","ifcGuid":"3CGMPQxKTJ_x1EmCqkjANa","ifcClass":"IfcGeographicElement","buildingId":"site","buildingName":"Urbanización y parcela","sourceDocumentId":"URB-20260731","sourceRepresentationKind":"documentary_mesh"} | site_002

# IfcGroup (30)
Name | Description
Urbanización | Grupo de visualización y consulta por disciplina.
Equipos | Grupo de visualización y consulta por disciplina.
Terreno existente | Grupo de visualización y consulta por disciplina.
Arquitectura | Grupo de visualización y consulta por disciplina.
Cimentación | Grupo de visualización y consulta por disciplina.
Estructura | Grupo de visualización y consulta por disciplina.
Envolventes acústicas de equipos | Grupo de visualización y consulta por disciplina.
Zona de separación de aire | Equipos, cimentaciones y referencias de planos coordinadas documentalmente.
BIM · Arquitectura | Capa independiente de visualización y clasificación funcional.
BIM · Estructura | Capa independiente de visualización y clasificación funcional.
BIM · Equipos | Capa independiente de visualización y clasificación funcional.
BIM · Envolventes de equipos | Capa independiente de visualización y clasificación funcional.
BIM · Cimentaciones | Capa independiente de visualización y clasificación funcional.
BIM · Viales y pavimentos | Capa independiente de visualización y clasificación funcional.
BIM · Urbanización | Capa independiente de visualización y clasificación funcional.
BIM · Servicios auxiliares | Capa independiente de visualización y clasificación funcional.
BIM · Referencias documentales | Capa independiente de visualización y clasificación funcional.
BIM · Terreno existente | Capa independiente de visualización y clasificación funcional.
Esquemas provisionales · no para construcción | Esquema provisional solicitado para coordinación visual. No apto para construcción, fabricación, compra o medición; las magnitudes de malla no son cantidades de obra.
C33 · soporte y dos tramos ilustrativos | Esquema provisional solicitado para coordinación visual. No apto para construcción, fabricación, compra o medición; las magnitudes de malla no son cantidades de obra.
BIM · Vallado perimetral | Cerramiento perimetral independiente: bases, postes y malla; aperturas de acceso conservadas.
BIM · Galería de nitrógeno · esquema | Esquema provisional de coordinación autorizado por el cliente. Tuberías, soportes, alumbrado e hidrantes con dimensiones y posiciones orientativas; no para construcción ni cómputo de cantidades.
BIM · Nitrógeno · tramo enterrado | Esquema provisional de coordinación autorizado por el cliente. Tuberías, soportes, alumbrado e hidrantes con dimensiones y posiciones orientativas; no para construcción ni cómputo de cantidades.
BIM · Alumbrado exterior | Esquema provisional de coordinación autorizado por el cliente. Tuberías, soportes, alumbrado e hidrantes con dimensiones y posiciones orientativas; no para construcción ni cómputo de cantidades.
BIM · Hidrantes exteriores | Esquema provisional de coordinación autorizado por el cliente. Tuberías, soportes, alumbrado e hidrantes con dimensiones y posiciones orientativas; no para construcción ni cómputo de cantidades.
BIM · Entorno · superficie exterior | Entorno de coordinación: trazados derivados de las fuentes indicadas por elemento; cotas, espesores, acabados y mobiliario orientativos cuando no están documentados. No acredita propiedad, servidumbres ni cantidades de obra y no es una base de construcción.
BIM · Entorno · viales y aceras | Entorno de coordinación: trazados derivados de las fuentes indicadas por elemento; cotas, espesores, acabados y mobiliario orientativos cuando no están documentados. No acredita propiedad, servidumbres ni cantidades de obra y no es una base de construcción.
BIM · Entorno · parcelas catastrales | Entorno de coordinación: trazados derivados de las fuentes indicadas por elemento; cotas, espesores, acabados y mobiliario orientativos cuando no están documentados. No acredita propiedad, servidumbres ni cantidades de obra y no es una base de construcción.
BIM · Entorno · aparcamientos y luminarias | Entorno de coordinación: trazados derivados de las fuentes indicadas por elemento; cotas, espesores, acabados y mobiliario orientativos cuando no están documentados. No acredita propiedad, servidumbres ni cantidades de obra y no es una base de construcción.
SL1201 · estructura de soporte según planos

# IfcHeatExchanger: Envolvente de equipo (3)
In: Parcela industrial Jinhong
Description: Equipo industrial con detalle geométrico provisional; PredefinedType: USERDEFINED; Document: Plano del fabricante: cargas de equipos; Plano del fabricante: implantación de equipos · referencia E7; Cimentaciones de equipos y pedestales del fabricante · revisión recibida 04/09/2026; Fotografía de referencia aportada · 01; Fotografía de referencia aportada · 02; Fotografía de referencia aportada · 06; Group: Equipos; Zona de separación de aire; BIM · Equipos
JH_DimensionesDelModelo - Extensión de la malla en X: 3.09497 m; Extensión de la malla en Y: 2.68506 m; Extensión de la malla en Z: 11.5 m; Cota inferior de visualización: 286.615 m; Cota superior de visualización: 298.115 m
JH_MagnitudesGeometricas - ExtensionX: 3.09497 m; ExtensionY: 2.68506 m; ExtensionZ: 11.5 m; SuperficieDeLaMalla: 2739.82 m2; VolumenGeometrico: 4.15071 m3
JH_CoordinacionCimentaciones - Relacion: Correspondencia documental; no verifica anclajes ni cotas de montaje.
JH_InformacionBIM - buildingId: process_plant; buildingName: Planta de proceso; level: Apoyo relativo +0.515 m; cero absoluto provisional; category: Equipo industrial con detalle geométrico provisional; ifcClass: IfcHeatExchanger; material: {"name":"No especificado","source":"Sin especificación de material en la documentación revisada","status":"unknown"}; source: {"documentId":"EQ-CARGAS-20260825","title":"Plano del fabricante: cargas de equipos","sheet":"Espacio modelo; número de plano no identificado","date":"2026-08-25"}; status: provisional; positioning: {"Estado de la planta":"Derivado del CAD y del giro de implantación","Nivel relativo del apoyo (m)":0.515,"Estado del nivel relativo":"Documentado en el plano de cimentaciones","Cero absoluto de visualización (m)":286.1,"Estado del cero absoluto":"Provisional","Cota del apoyo de visualización (m)":286.615,"Desplazamiento aplicado a la malla (m)":0.5150000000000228,"Criterio":"Nivel de apoyo relativo documentado. Se adopta el cero de proceso a 286,10 m solo para visualización; la equivalencia absoluta no está confirmada. No se añade un espesor de montaje sin cota del fabricante."}; issues: ["El haz aleteado modelado mide aproximadamente 2,825 × 2,349 m en planta. El contorno general documentado de 3,418 × 2,848 m incluye elementos no detallados; no se sustituye por el tamaño del haz.","Espesor de aleta de 3 mm adoptado exclusivamente para visualización; no es un espesor de fabricación documentado.","Longitud activa de las aletas, separación al suelo, bastidor y altura de apoyos sin cotas verificadas.","La sección de planta se prolonga desde 0 hasta 11,5 m; la altura total está documentada, pero su distribución vertical es provisional.","Compatibilidad entre el detalle de planta de abril y las dimensiones generales de agosto pendiente de confirmación del fabricante.","Cinco pedestales DZ8 por vaporizador; el acabado de grout de 50 mm termina en +0,515. La cota -2,400 de planta no concuerda con -2,000 del fondo de sección.","El cero absoluto de la revisión no está definido; 286,10 m sigue siendo una hipótesis de coordinación.","Se alinea el punto inferior del conjunto del equipo, incluidos los pies ya representados, con la superficie de apoyo terminada; no se añade un espesor de calzos, placa o grout del fabricante no documentado."]; ifcAssociations: {"material":false,"document":true,"quantities":true,"containerGuid":"17utmjd_LKsAVvPyuSUhFt","containerName":"Parcela industrial Jinhong"}; installationSource: {"documentId":"LHD2609-JG00100-20260904","title":"Cimentaciones y pedestales de equipos · revisión recibida 04/09/2026","date":"2026-09-04","sheet":"8 / 8-8","sourceHandles":["1FF47","1FF4A","1FF4D","1FF50","1FF58"]}; representationKind: equipment; visualLayer: {"id":"equipment","name":"Equipos"}; materialAppearance: {"profileId":"equipment_silver_fins","name":"Vaporizador · aletas gris plata de referencia","materialName":"No especificado","physicalMaterialStatus":"unknown","physicalMaterialSource":"Sin especificación de material en la documentación revisada","appearanceStatus":"referencia_fotografica_provisional","appearanceBasis":"Fotografías reales aportadas el 08/09/2026, sin fecha de toma ni emplazamiento verificados. Aletas verticales gris plata y reflejos neutros en las fotografías 01, 02 y 06. El bastidor exterior, travesaños y diagonales son detalles pendientes de planos específicos. Tono y parámetros de visualización orientativos; no especifican pintura, aleación ni dimensiones.","note":"La apariencia gráfica no modifica ni confirma la especificación física del material."}; componentSeparation: {"status":"aletas_combinadas_sin_bastidor","note":"120 tubos aleteados combinados. No existe una cabina exterior; bastidor y apoyos del fabricante sin geometría verificada."}; classification: {"layerId":"equipment","layerName":"Equipos","role":"Equipo industrial con detalle geométrico provisional","basis":"Clasificación por función del elemento; no modifica las especificaciones documentales."}; layerId: equipment; appearance: {"profileId":"equipment_silver_fins","name":"Vaporizador · aletas gris plata de referencia","status":"referencia_fotografica_provisional","basis":"Fotografías reales aportadas el 08/09/2026, sin fecha de toma ni emplazamiento verificados. Aletas verticales gris plata y reflejos neutros en las fotografías 01, 02 y 06. El bastidor exterior, travesaños y diagonales son detalles pendientes de planos específicos. Tono y parámetros de visualización orientativos; no especifican pintura, aleación ni dimensiones.","physicalMaterialUnchanged":true}; photoAppearanceReview: {"receivedDate":"2026-09-08","referenceIds":["xinrui-jinhong-vaporizers","foto-usuario-20260908-01","foto-usuario-20260908-02","foto-usuario-20260908-06"],"use":"Color, brillo y lectura de superficies. Sin cambios de geometría o dimensiones.","geometryConfirmedByPhotos":false}
JH_Trazabilidad - Referencia en el plano del fabricante: 8; Documento de origen: Plano del fabricante: cargas de equipos · 2026-08-25 · Espacio modelo; número de plano no identificado; Documento CAD derivado: Conversión DXF del plano de cargas de equipos · 2026-08-25 · espacio modelo; Capa CAD de referencia: Anotaciones y contornos de equipos; Cota de altura del fabricante (traducción): Altura del equipo: 11.5m; Altura (m): 11.5; Origen de las dimensiones: Plano de cargas del fabricante de 2026-08-25: lectura directa del contorno CAD cerrado y de la cota de altura del equipo.; Grado de definición: Planta derivada del CAD, altura total documentada y alturas parciales provisionales.; Alcance de la geometría: Geometría compuesta con perfiles CAD y distribución vertical provisional; véase Detalle geométrico.; Origen de la posición: Punto de referencia del fabricante: entidad CIRCLE, handle 98, en la esquina inferior izquierda de la zona de equipos. Los ejes X e Y son locales y se giran para su implantación UTM.; Hipótesis de modelado: Nivel de apoyo relativo documentado. Se adopta el cero de proceso a 286,10 m solo para visualización; la equivalencia absoluta no está confirmada. No se añade un espesor de montaje sin cota del fabricante.; Observaciones: Masa permanente indicada: 6 800 kg; el plano recoge además una carga variable de 8 200 kg. Se indican cinco puntos de transmisión de carga.; Masa propia indicada (kg): 6800; Dimensión X local (m): 3.418; Dimensión Y local (m): 2.848; Dimensiones de la plataforma de equipos (m): 27 × 57 m; dimensiones acotadas en el plano general.; Implantación de la plataforma de equipos: El punto de referencia del fabricante coincide con la esquina suroeste de la zona de equipos. Giro local de −7,82824° para la implantación en coordenadas UTM.; Estado de la cota de instalación: Nivel de apoyo relativo documentado. Se adopta el cero de proceso a 286,10 m solo para visualización; la equivalencia absoluta no está confirmada. No se añade un espesor de montaje sin cota del fabricante.; Convención de coordenadas: Coordenadas locales del proyecto en metros. Añadir (729400, 4301550, 285) para recuperar las coordenadas UTM y las cotas del plano.; Disciplina: Equipos; Clase IFC: IfcHeatExchanger; Fase del modelo: Revisión de la zona de separación de aire · septiembre de 2026; Representación geométrica IFC: Sólido IFC4 mediante malla triangular cerrada; Aplicabilidad a mediciones: Magnitudes de la geometría representada; no son cantidades de material, obra, compra, capacidad útil ni fabricación. En geometrías compuestas se suman superficies y volúmenes de partes y pueden existir solapes no depurados.; Carga variable indicada por el fabricante (kg): 8200; Material: No especificado; Estado de la información: provisional; Detalle geométrico: 120 centros y trazos de aleta por unidad derivados directamente de los vectores CAD; perfil de espesor provisional.; Incidencias del detalle: ["Nivel de apoyo relativo documentado. Se adopta el cero de proceso a 286,10 m solo para visualización; la equivalencia absoluta no está confirmada. No se añade un espesor de montaje sin cota del fabricante.","El haz aleteado modelado mide aproximadamente 2,825 × 2,349 m en planta. El contorno general documentado de 3,418 × 2,848 m incluye elementos no detallados; no se sustituye por el tamaño del haz.","Espesor de aleta de 3 mm adoptado exclusivamente para visualización; no es un espesor de fabricación documentado.","Longitud activa de las aletas, separación al suelo, bastidor y altura de apoyos sin cotas verificadas.","La sección de planta se prolonga desde 0 hasta 11,5 m; la altura total está documentada, pero su distribución vertical es provisional.","Compatibilidad entre el detalle de planta de abril y las dimensiones generales de agosto pendiente de confirmación del fabricante."]; Extensión X del haz aleteado representado (m): 2.82496; Extensión Y del haz aleteado representado (m): 2.34896; Nivel relativo de apoyo documentado (m): 0.515; Fuente del nivel de apoyo: {"documentId":"LHD2609-JG00100-20260904","title":"Cimentaciones y pedestales de equipos · revisión recibida 04/09/2026","date":"2026-09-04","sheet":"8 / 8-8","sourceHandles":["1FF47","1FF4A","1FF4D","1FF50","1FF58"]}; Criterio de instalación: Nivel de apoyo relativo documentado. Se adopta el cero de proceso a 286,10 m solo para visualización; la equivalencia absoluta no está confirmada. No se añade un espesor de montaje sin cota del fabricante.; Capa BIM: Equipos; Acabado de visualización: Vaporizador · aletas gris plata de referencia; Estado del acabado: referencia_fotografica_provisional; Categoria: Equipo industrial con detalle geométrico provisional; ClaseIFC: IfcHeatExchanger; EstadoDeInformacion: provisional; DocumentoFuente: {"documentId":"EQ-CARGAS-20260825","title":"Plano del fabricante: cargas de equipos","sheet":"Espacio modelo; número de plano no identificado","date":"2026-08-25"}; IncidenciasPendientes: ["El haz aleteado modelado mide aproximadamente 2,825 × 2,349 m en planta. El contorno general documentado de 3,418 × 2,848 m incluye elementos no detallados; no se sustituye por el tamaño del haz.","Espesor de aleta de 3 mm adoptado exclusivamente para visualización; no es un espesor de fabricación documentado.","Longitud activa de las aletas, separación al suelo, bastidor y altura de apoyos sin cotas verificadas.","La sección de planta se prolonga desde 0 hasta 11,5 m; la altura total está documentada, pero su distribución vertical es provisional.","Compatibilidad entre el detalle de planta de abril y las dimensiones generales de agosto pendiente de confirmación del fabricante.","Cinco pedestales DZ8 por vaporizador; el acabado de grout de 50 mm termina en +0,515. La cota -2,400 de planta no concuerda con -2,000 del fondo de sección.","El cero absoluto de la revisión no está definido; 286,10 m sigue siendo una hipótesis de coordinación.","Se alinea el punto inferior del conjunto del equipo, incluidos los pies ya representados, con la superficie de apoyo terminada; no se añade un espesor de calzos, placa o grout del fabricante no documentado."]; UsoDeLasMagnitudes: Geometría de coordinación. Los volúmenes de referencia y subcomponentes no son cantidades de material ni componentes de fabricación certificados.
JH_CriterioDePosicion - PosicionYEstado: {"Estado de la planta":"Derivado del CAD y del giro de implantación","Nivel relativo del apoyo (m)":0.515,"Estado del nivel relativo":"Documentado en el plano de cimentaciones","Cero absoluto de visualización (m)":286.1,"Estado del cero absoluto":"Provisional","Cota del apoyo de visualización (m)":286.615,"Desplazamiento aplicado a la malla (m)":0.5150000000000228,"Criterio":"Nivel de apoyo relativo documentado. Se adopta el cero de proceso a 286,10 m solo para visualización; la equivalencia absoluta no está confirmada. No se añade un espesor de montaje sin cota del fabricante."}
JH_EvidenciaDeMaterial - name: No especificado; source: Sin especificación de material en la documentación revisada; status: unknown
JH_DimensionesDocumentadas - Dimensión X local del contorno CAD: 3.418 m; Dimensión Y local del contorno CAD: 2.848 m; Altura acotada: 11.5 m; Cota relativa de la superficie de apoyo: 0.515 m
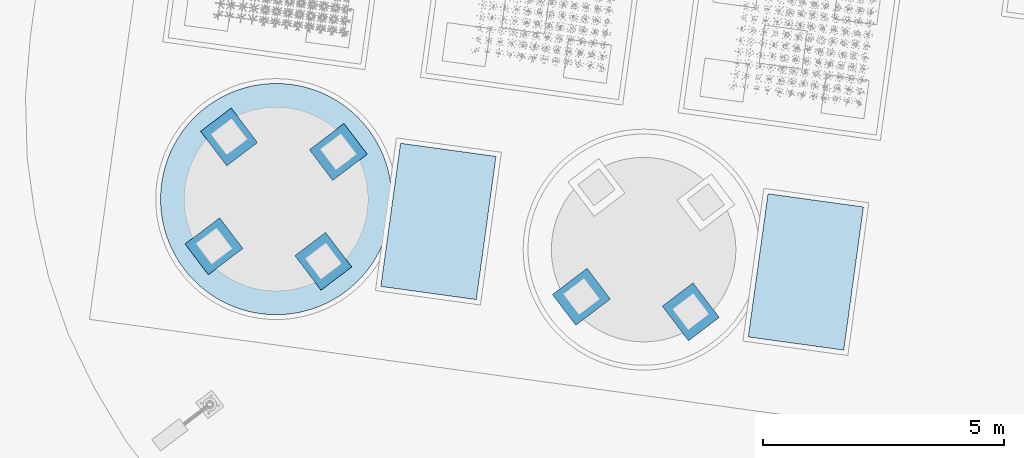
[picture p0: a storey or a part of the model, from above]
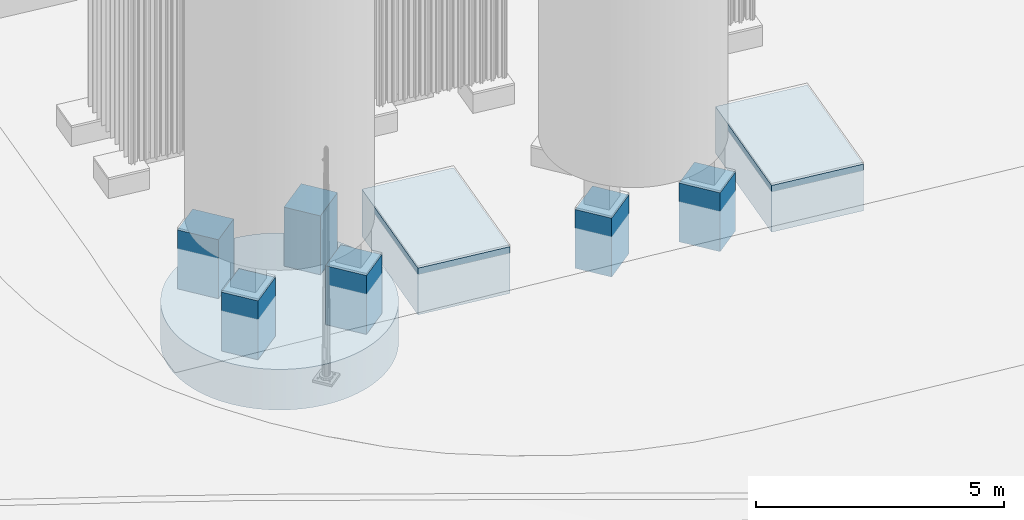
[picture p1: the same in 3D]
Properties of the parts of a building model (IFC4), part 89 of 134

# IfcHeatExchanger: Envolvente de equipo (3)
Name | ElementosDeCimentacion = foundationIds | dimensions | geometryMetrics | detailGeometry | visualizationIdentity | Identificador del fabricante o del modelo = Identificador del objeto = Identificador | Identificadores CAD del contorno (handles) | Identificador CAD de la cota de altura (handle) | source | referenceEnvelopePadM
Vaporizador de nitrógeno líquido LV1802B | ["found_0904_1b97527a137752","found_0904_d0f045b5660f21","found_0904_e186e53af6b768","found_0904_85ed74c85618e3","found_0904_6def6a5a7fdab6","found_0904_7ef187068a20b2","found_0904_2c4c84af4d4d91","found_0904_c8566969e202a4","found_0904_feeaf076bc98f8","found_0904_9636fe48a7f337","found_0904_5af42dcdd2d975","found_0904_71372f1c9ab124"] | {"documented":[{"label":"Dimensión X local del contorno CAD","value":3.418,"unit":"m","source":"EQ-CARGAS-20260825 · contorno CAD · handles 44E","status":"derivado"},{"label":"Dimensión Y local del contorno CAD","value":2.848,"unit":"m","source":"EQ-CARGAS-20260825 · contorno CAD · handles 44E","status":"derivado"},{"label":"Altura acotada","value":11.5,"unit":"m","source":"EQ-CARGAS-20260825 · handle 2678","status":"documentado"},{"label":"Cota relativa de la superficie de apoyo","value":0.515,"unit":"m","source":"LHD2609-JG00100-20260904 · sección 8 / 8-8 · 1FF47, 1FF4A, 1FF4D, 1FF50, 1FF58","status":"documentado"}],"geometry":[{"label":"Extensión de la malla en X","value":3.094965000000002,"unit":"m","source":"Geometría releída del IFC; datum absoluto de proceso provisional","status":"derivado"},{"label":"Extensión de la malla en Y","value":2.68506,"unit":"m","source":"Geometría releída del IFC; datum absoluto de proceso provisional","status":"derivado"},{"label":"Extensión de la malla en Z","value":11.5,"unit":"m","source":"Geometría releída del IFC; datum absoluto de proceso provisional","status":"derivado"},{"label":"Cota inferior de visualización","value":286.615,"unit":"m","source":"Geometría releída del IFC; datum absoluto de proceso provisional","status":"derivado"},{"label":"Cota superior de visualización","value":298.115,"unit":"m","source":"Geometría releída del IFC; datum absoluto de proceso provisional","status":"derivado"}],"notes":["Las extensiones de la malla se miden en los ejes del proyecto tras el giro de implantación; no sustituyen las dimensiones locales del fabricante.","La envolvente, su volumen y los espesores de visualización no son volúmenes de material ni cantidades de compra, construcción o fabricación.","Las dimensiones documentadas distinguen cotas explícitas y medidas extraídas de contornos CAD; las dimensiones geométricas describen únicamente la malla publicada.","Las extensiones de la malla refinada y las dimensiones documentadas del contorno o bastidor tienen distinto alcance; las cotas parciales del detalle son provisionales."]} | {"boundingBoxM":{"min":[40.424519,35.146498,1.615],"max":[43.519484,37.831558,13.115]},"extentsM":[3.094965,2.68506,11.5],"meshSurfaceM2":2739.822904,"meshVolumeM3":4.150712,"closedSolid":true,"basis":"Magnitudes de las mallas representadas, no cantidades certificadas de obra, compra o fabricación. Las partes pueden compartir superficies; no se suman como un despiece de materiales."} | {"source":{"documentId":"EQ-IMPLANTACION-20260430","title":"Plano del fabricante: implantación de equipos · referencia E7","sheet":"Espacio modelo; referencia E7 en el nombre del archivo","date":"2026-04-30","insertHandle":"8361F"},"revision":"Detalle de planta E7 2026-04-30; altura global 2026-08-25","horizontalStatus":"120 centros y trazos de aleta por unidad derivados directamente de los vectores CAD; perfil de espesor provisional.","verticalRule":"Extrusión conceptual continua entre z=0 y z=11,5 m respecto al fondo del equipo. No se asignan alturas inventadas a apoyos ni a bastidores.","status":"provisional","unconfirmedDimensions":["Espesor de aleta de 3 mm adoptado exclusivamente para visualización; no es un espesor de fabricación documentado.","Longitud activa de las aletas, separación al suelo, bastidor y altura de apoyos sin cotas verificadas.","La sección de planta se prolonga desde 0 hasta 11,5 m; la altura total está documentada, pero su distribución vertical es provisional.","Compatibilidad entre el detalle de planta de abril y las dimensiones generales de agosto pendiente de confirmación del fabricante."],"array":{"units":120,"columns":12,"rows":10,"finTraceCounts":{"6":16,"10":24,"8":24,"12":56}},"nominalVisualizationFinThicknessM":0.003,"documentedOverallHeightM":11.5,"referenceEnvelopePadM":{"min":[6.532,6.277,0],"max":[9.95,9.125,11.5]},"measurementBasis":"Geometría de visualización; no utilizar para peso, superficie de intercambio ni medición de suministro.","heightSource":{"documentId":"EQ-CARGAS-20260825","title":"Plano del fabricante: cargas de equipos","sheet":"Espacio modelo","date":"2026-08-25"},"partsAreBOM":false,"partCount":120,"sourcePartHandles":[{"partId":"tubo-aleteado-001","sourceHandles":["972E6","971B9","96CFA","971BA","971BB","971BC","971BD","971BE"]},{"partId":"tubo-aleteado-002","sourceHandles":["972E3","971B1","96CF8","971B2","971B3","971B5","971B7","971B8"]},{"partId":"tubo-aleteado-003","sourceHandles":["972E7","9723A","96D04","9723B","9723C","9723D","9723E","97240"]},{"partId":"tubo-aleteado-004","sourceHandles":["972E4","97241","96D02","96D09","97242","97243","97244","97245"]},{"partId":"tubo-aleteado-005","sourceHandles":["9736A","970F2","96D07","96D53","970F3","970F4","970F5","970F7","970F8","970FA","970FB","970FC"]},{"partId":"tubo-aleteado-006","sourceHandles":["97367","970FD","96D51","96D80","970FE","970FF","97100","97101","97102","97104","97105","97106"]},{"partId":"tubo-aleteado-007","sourceHandles":["9736B","97107","96D7E","96DAD","97108","97109","9710A","9710B","9710C","9710E","9710F","97110"]},{"partId":"tubo-aleteado-008","sourceHandles":["97368","97111","96DAB","96DDA","97112","97113","97114","97115","97116","97118","97119","9711A"]},{"partId":"tubo-aleteado-009","sourceHandles":["973A6","9711B","96DD8","96E07","9711C","9711D","9711E","9711F","97120","97122","97123","97124"]},{"partId":"tubo-aleteado-010","sourceHandles":["973A3","97125","96E05","96E34","97126","97127","97128","97129","9712A","9712C","9712D","9712E"]},{"partId":"tubo-aleteado-011","sourceHandles":["973A7","9712F","96E32","96E61","97130","97131","97132","97133","97134","97136","97137","97138"]},{"partId":"tubo-aleteado-012","sourceHandles":["973A4","97139","96E5F","9713A","9713B","9713C","9713D","9713E","9713F","97140","97141","97142"]},{"partId":"tubo-aleteado-013","sourceHandles":["972E0","971AC","96CE6","96CFB","971AD","971AE","971AF","971B0"]},{"partId":"tubo-aleteado-014","sourceHandles":["972DD","971A5","96CE4","96CF9","971A6","971A7","971A8","971A9","971AA","971AB"]},{"partId":"tubo-aleteado-015","sourceHandles":["972E1","9722E","96CF0","96D05","9722F","97230","97231","97232","97233","97234"]},{"partId":"tubo-aleteado-016","sourceHandles":["972DE","97235","96CEE","96CF5","96D03","96D0A","97236","97237","97238","97239"]},{"partId":"tubo-aleteado-017","sourceHandles":["97364","970AA","96CF3","96D08","96D4E","96D54","970AB","970AC","970AD","970AE","970AF","970B0","970B1","970B2"]},{"partId":"tubo-aleteado-018","sourceHandles":["97361","970B3","96D4C","96D52","96D7B","96D81","970B4","970B5","970B6","970B7","970B8","970B9","970BA","970BB"]},{"partId":"tubo-aleteado-019","sourceHandles":["97365","970BC","96D79","96D7F","96DA8","96DAE","970BD","970BE","970BF","970C0","970C1","970C2","970C3","970C4"]},{"partId":"tubo-aleteado-020","sourceHandles":["97362","970C5","96DA6","96DAC","96DD5","96DDB","970C6","970C7","970C8","970C9","970CA","970CB","970CC","970CD"]},{"partId":"tubo-aleteado-021","sourceHandles":["973A0","970CE","96DD3","96DD9","96E02","96E08","970CF","970D0","970D1","970D2","970D3","970D4","970D5","970D6"]},{"partId":"tubo-aleteado-022","sourceHandles":["9739D","970D7","96E00","96E06","96E2F","96E35","970D8","970D9","970DA","970DB","970DC","970DD","970DE","970DF"]},{"partId":"tubo-aleteado-023","sourceHandles":["973A1","970E0","96E2D","96E33","96E5C","96E62","970E1","970E2","970E3","970E4","970E5","970E6","970E7","970E8"]},{"partId":"tubo-aleteado-024","sourceHandles":["9739E","970E9","96E5A","96E60","970EA","970EB","970EC","970ED","970EE","970EF","970F0","970F1"]},{"partId":"tubo-aleteado-025","sourceHandles":["972DA","971A0","96CD2","96CE7","971A1","971A2","971A3","971A4"]},{"partId":"tubo-aleteado-026","sourceHandles":["972D7","97199","96CD0","96CE5","9719A","9719B","9719C","9719D","9719E","9719F"]},{"partId":"tubo-aleteado-027","sourceHandles":["972DB","97222","96CDC","96CF1","97223","97224","97225","97226","97227","97228"]},{"partId":"tubo-aleteado-028","sourceHandles":["972D8","97229","96CDA","96CE1","96CEF","96CF6","9722A","9722B","9722C","9722D"]},{"partId":"tubo-aleteado-029","sourceHandles":["9735E","97062","96CDF","96CF4","96D49","96D4F","97063","97064","97065","97066","97067","97068","97069","9706A"]},{"partId":"tubo-aleteado-030","sourceHandles":["9735B","9706B","96D47","96D4D","96D76","96D7C","9706C","9706D","9706E","9706F","97070","97071","97072","97073"]},{"partId":"tubo-aleteado-031","sourceHandles":["9735F","97074","96D74","96D7A","96DA3","96DA9","97075","97076","97077","97078","97079","9707A","9707B","9707C"]},{"partId":"tubo-aleteado-032","sourceHandles":["9735C","9707D","96DA1","96DA7","96DD0","96DD6","9707E","9707F","97080","97081","97082","97083","97084","97085"]},{"partId":"tubo-aleteado-033","sourceHandles":["9739A","97086","96DCE","96DD4","96DFD","96E03","97087","97088","97089","9708A","9708B","9708C","9708D","9708E"]},{"partId":"tubo-aleteado-034","sourceHandles":["97397","9708F","96DFB","96E01","96E2A","96E30","97090","97091","97092","97093","97094","97095","97096","97097"]},{"partId":"tubo-aleteado-035","sourceHandles":["9739B","97098","96E28","96E2E","96E57","96E5D","97099","9709A","9709B","9709C","9709D","9709E","9709F","970A0"]},{"partId":"tubo-aleteado-036","sourceHandles":["97398","970A1","96E55","96E5B","970A2","970A3","970A4","970A5","970A6","970A7","970A8","970A9"]},{"partId":"tubo-aleteado-037","sourceHandles":["972D4","97194","96CBE","96CD3","97195","97196","97197","97198"]},{"partId":"tubo-aleteado-038","sourceHandles":["972D1","9718D","96CBC","96CD1","9718E","9718F","97190","97191","97192","97193"]},{"partId":"tubo-aleteado-039","sourceHandles":["972D5","97216","96CC8","96CDD","97217","97218","97219","9721A","9721B","9721C"]},{"partId":"tubo-aleteado-040","sourceHandles":["972D2","9721D","96CC6","96CCD","96CDB","96CE2","9721E","9721F","97220","97221"]},{"partId":"tubo-aleteado-041","sourceHandles":["97358","9701A","96CCB","96CE0","96D44","96D4A","9701B","9701C","9701D","9701E","9701F","97020","97021","97022"]},{"partId":"tubo-aleteado-042","sourceHandles":["97355","97023","96D42","96D48","96D71","96D77","97024","97025","97026","97027","97028","97029","9702A","9702B"]},{"partId":"tubo-aleteado-043","sourceHandles":["97359","9702C","96D6F","96D75","96D9E","96DA4","9702D","9702E","9702F","97030","97031","97032","97033","97034"]},{"partId":"tubo-aleteado-044","sourceHandles":["97356","97035","96D9C","96DA2","96DCB","96DD1","97036","97037","97038","97039","9703A","9703B","9703C","9703D"]},{"partId":"tubo-aleteado-045","sourceHandles":["97394","9703E","96DC9","96DCF","96DF8","96DFE","9703F","97040","97041","97042","97043","97044","97045","97046"]},{"partId":"tubo-aleteado-046","sourceHandles":["97391","97047","96DF6","96DFC","96E25","96E2B","97048","97049","9704A","9704B","9704C","9704D","9704E","9704F"]},{"partId":"tubo-aleteado-047","sourceHandles":["97395","97050","96E23","96E29","96E52","96E58","97051","97052","97053","97054","97055","97056","97057","97058"]},{"partId":"tubo-aleteado-048","sourceHandles":["97392","97059","96E50","96E56","9705A","9705B","9705C","9705D","9705E","9705F","97060","97061"]},{"partId":"tubo-aleteado-049","sourceHandles":["972CE","97188","96CAA","96CBF","97189","9718A","9718B","9718C"]},{"partId":"tubo-aleteado-050","sourceHandles":["972CB","97181","96CA8","96CBD","97182","97183","97184","97185","97186","97187"]},{"partId":"tubo-aleteado-051","sourceHandles":["972CF","9720A","96CB4","96CC9","9720B","9720C","9720D","9720E","9720F","97210"]},{"partId":"tubo-aleteado-052","sourceHandles":["972CC","97211","96CB2","96CB9","96CC7","96CCE","97212","97213","97214","97215"]},{"partId":"tubo-aleteado-053","sourceHandles":["97352","96FD2","96CB7","96CCC","96D3F","96D45","96FD3","96FD4","96FD5","96FD6","96FD7","96FD8","96FD9","96FDA"]},{"partId":"tubo-aleteado-054","sourceHandles":["9734F","96FDB","96D3D","96D43","96D6C","96D72","96FDC","96FDD","96FDE","96FDF","96FE0","96FE1","96FE2","96FE3"]},{"partId":"tubo-aleteado-055","sourceHandles":["97353","96FE4","96D6A","96D70","96D99","96D9F","96FE5","96FE6","96FE7","96FE8","96FE9","96FEA","96FEB","96FEC"]},{"partId":"tubo-aleteado-056","sourceHandles":["97350","96FED","96D97","96D9D","96DC6","96DCC","96FEE","96FEF","96FF0","96FF1","96FF2","96FF3","96FF4","96FF5"]},{"partId":"tubo-aleteado-057","sourceHandles":["9738E","96FF6","96DC4","96DCA","96DF3","96DF9","96FF7","96FF8","96FF9","96FFA","96FFB","96FFC","96FFD","96FFE"]},{"partId":"tubo-aleteado-058","sourceHandles":["9738B","96FFF","96DF1","96DF7","96E20","96E26","97000","97001","97002","97003","97004","97005","97006","97007"]},{"partId":"tubo-aleteado-059","sourceHandles":["9738F","97008","96E1E","96E24","96E4D","96E53","97009","9700A","9700B","9700C","9700D","9700E","9700F","97010"]},{"partId":"tubo-aleteado-060","sourceHandles":["9738C","97011","96E4B","96E51","97012","97013","97014","97015","97016","97017","97018","97019"]},{"partId":"tubo-aleteado-061","sourceHandles":["972C8","9717C","96C96","96CAB","9717D","9717E","9717F","97180"]},{"partId":"tubo-aleteado-062","sourceHandles":["972C5","97175","96C94","96CA9","97176","97177","97178","97179","9717A","9717B"]},{"partId":"tubo-aleteado-063","sourceHandles":["972C9","971FE","96CA0","96CB5","971FF","97200","97201","97202","97203","97204"]},{"partId":"tubo-aleteado-064","sourceHandles":["972C6","97205","96C9E","96CA5","96CB3","96CBA","97206","97207","97208","97209"]},{"partId":"tubo-aleteado-065","sourceHandles":["9734C","96F8A","96CA3","96CB8","96D3A","96D40","96F8B","96F8C","96F8D","96F8E","96F8F","96F90","96F91","96F92"]},{"partId":"tubo-aleteado-066","sourceHandles":["97349","96F93","96D38","96D3E","96D67","96D6D","96F94","96F95","96F96","96F97","96F98","96F99","96F9A","96F9B"]},{"partId":"tubo-aleteado-067","sourceHandles":["9734D","96F9C","96D65","96D6B","96D94","96D9A","96F9D","96F9E","96F9F","96FA0","96FA1","96FA2","96FA3","96FA4"]},{"partId":"tubo-aleteado-068","sourceHandles":["9734A","96FA5","96D92","96D98","96DC1","96DC7","96FA6","96FA7","96FA8","96FA9","96FAA","96FAB","96FAC","96FAD"]},{"partId":"tubo-aleteado-069","sourceHandles":["97388","96FAE","96DBF","96DC5","96DEE","96DF4","96FAF","96FB0","96FB1","96FB2","96FB3","96FB4","96FB5","96FB6"]},{"partId":"tubo-aleteado-070","sourceHandles":["97385","96FB7","96DEC","96DF2","96E1B","96E21","96FB8","96FB9","96FBA","96FBB","96FBC","96FBD","96FBE","96FBF"]},{"partId":"tubo-aleteado-071","sourceHandles":["97389","96FC0","96E19","96E1F","96E48","96E4E","96FC1","96FC2","96FC3","96FC4","96FC5","96FC6","96FC7","96FC8"]},{"partId":"tubo-aleteado-072","sourceHandles":["97386","96FC9","96E46","96E4C","96FCA","96FCB","96FCC","96FCD","96FCE","96FCF","96FD0","96FD1"]},{"partId":"tubo-aleteado-073","sourceHandles":["972C2","97170","96C82","96C97","97171","97172","97173","97174"]},{"partId":"tubo-aleteado-074","sourceHandles":["972BF","97169","96C80","96C95","9716A","9716B","9716C","9716D","9716E","9716F"]},{"partId":"tubo-aleteado-075","sourceHandles":["972C3","971F2","96C8C","96CA1","971F3","971F4","971F5","971F6","971F7","971F8"]},{"partId":"tubo-aleteado-076","sourceHandles":["972C0","971F9","96C8A","96C91","96C9F","96CA6","971FA","971FB","971FC","971FD"]},{"partId":"tubo-aleteado-077","sourceHandles":["97346","96F42","96C8F","96CA4","96D35","96D3B","96F43","96F44","96F45","96F46","96F47","96F48","96F49","96F4A"]},{"partId":"tubo-aleteado-078","sourceHandles":["97343","96F4B","96D33","96D39","96D62","96D68","96F4C","96F4D","96F4E","96F4F","96F50","96F51","96F52","96F53"]},{"partId":"tubo-aleteado-079","sourceHandles":["97347","96F54","96D60","96D66","96D8F","96D95","96F55","96F56","96F57","96F58","96F59","96F5A","96F5B","96F5C"]},{"partId":"tubo-aleteado-080","sourceHandles":["97344","96F5D","96D8D","96D93","96DBC","96DC2","96F5E","96F5F","96F60","96F61","96F62","96F63","96F64","96F65"]},{"partId":"tubo-aleteado-081","sourceHandles":["97382","96F66","96DBA","96DC0","96DE9","96DEF","96F67","96F68","96F69","96F6A","96F6B","96F6C","96F6D","96F6E"]},{"partId":"tubo-aleteado-082","sourceHandles":["9737F","96F6F","96DE7","96DED","96E16","96E1C","96F70","96F71","96F72","96F73","96F74","96F75","96F76","96F77"]},{"partId":"tubo-aleteado-083","sourceHandles":["97383","96F78","96E14","96E1A","96E43","96E49","96F79","96F7A","96F7B","96F7C","96F7D","96F7E","96F7F","96F80"]},{"partId":"tubo-aleteado-084","sourceHandles":["97380","96F81","96E41","96E47","96F82","96F83","96F84","96F85","96F86","96F87","96F88","96F89"]},{"partId":"tubo-aleteado-085","sourceHandles":["972BC","97164","96C6E","96C83","97165","97166","97167","97168"]},{"partId":"tubo-aleteado-086","sourceHandles":["972B9","9715D","96C6C","96C81","9715E","9715F","97160","97161","97162","97163"]},{"partId":"tubo-aleteado-087","sourceHandles":["972BD","971E6","96C78","96C8D","971E7","971E8","971E9","971EA","971EB","971EC"]},{"partId":"tubo-aleteado-088","sourceHandles":["972BA","971ED","96C76","96C7D","96C8B","96C92","971EE","971EF","971F0","971F1"]},{"partId":"tubo-aleteado-089","sourceHandles":["97340","96EFA","96C7B","96C90","96D30","96D36","96EFB","96EFC","96EFD","96EFE","96EFF","96F00","96F01","96F02"]},{"partId":"tubo-aleteado-090","sourceHandles":["9733D","96F03","96D2E","96D34","96D5D","96D63","96F04","96F05","96F06","96F07","96F08","96F09","96F0A","96F0B"]},{"partId":"tubo-aleteado-091","sourceHandles":["97341","96F0C","96D5B","96D61","96D8A","96D90","96F0D","96F0E","96F0F","96F10","96F11","96F12","96F13","96F14"]},{"partId":"tubo-aleteado-092","sourceHandles":["9733E","96F15","96D88","96D8E","96DB7","96DBD","96F16","96F17","96F18","96F19","96F1A","96F1B","96F1C","96F1D"]},{"partId":"tubo-aleteado-093","sourceHandles":["9737C","96F1E","96DB5","96DBB","96DE4","96DEA","96F1F","96F20","96F21","96F22","96F23","96F24","96F25","96F26"]},{"partId":"tubo-aleteado-094","sourceHandles":["97379","96F27","96DE2","96DE8","96E11","96E17","96F28","96F29","96F2A","96F2B","96F2C","96F2D","96F2E","96F2F"]},{"partId":"tubo-aleteado-095","sourceHandles":["9737D","96F30","96E0F","96E15","96E3E","96E44","96F31","96F32","96F33","96F34","96F35","96F36","96F37","96F38"]},{"partId":"tubo-aleteado-096","sourceHandles":["9737A","96F39","96E3C","96E42","96F3A","96F3B","96F3C","96F3D","96F3E","96F3F","96F40","96F41"]},{"partId":"tubo-aleteado-097","sourceHandles":["972B6","97157","96C6F","97158","97159","9715A","9715B","9715C"]},{"partId":"tubo-aleteado-098","sourceHandles":["972B3","9714F","96C6D","97150","97151","97152","97153","97154","97155","97156"]},{"partId":"tubo-aleteado-099","sourceHandles":["972B7","971D7","96C79","971D8","971D9","971DA","971DB","971DC","971DD","971DE"]},{"partId":"tubo-aleteado-100","sourceHandles":["972B4","971DF","96C77","96C7E","971E0","971E1","971E2","971E3","971E4","971E5"]},{"partId":"tubo-aleteado-101","sourceHandles":["9733A","96EA3","96C7C","96D31","96EA4","96EA5","96EA6","96EA7","96EA8","96EA9","96EAA","96EAB","96EAC","96EAD"]},{"partId":"tubo-aleteado-102","sourceHandles":["97337","96EAE","96D2F","96D5E","96EAF","96EB0","96EB1","96EB2","96EB3","96EB4","96EB5","96EB6","96EB7","96EB8"]},{"partId":"tubo-aleteado-103","sourceHandles":["9733B","96EB9","96D5C","96D8B","96EBA","96EBB","96EBC","96EBD","96EBE","96EBF","96EC0","96EC1","96EC2","96EC3"]},{"partId":"tubo-aleteado-104","sourceHandles":["97338","96EC4","96D89","96DB8","96EC5","96EC6","96EC7","96EC8","96EC9","96ECA","96ECB","96ECC","96ECD","96ECE"]},{"partId":"tubo-aleteado-105","sourceHandles":["97376","96ECF","96DB6","96DE5","96ED0","96ED1","96ED2","96ED3","96ED4","96ED5","96ED6","96ED7","96ED8","96ED9"]},{"partId":"tubo-aleteado-106","sourceHandles":["97373","96EDA","96DE3","96E12","96EDB","96EDC","96EDD","96EDE","96EDF","96EE0","96EE1","96EE2","96EE3","96EE4"]},{"partId":"tubo-aleteado-107","sourceHandles":["97377","96EE5","96E10","96E3F","96EE6","96EE7","96EE8","96EE9","96EEA","96EEB","96EEC","96EED","96EEE","96EEF"]},{"partId":"tubo-aleteado-108","sourceHandles":["97374","96EF0","96E3D","96EF1","96EF2","96EF3","96EF4","96EF5","96EF6","96EF7","96EF8","96EF9"]},{"partId":"tubo-aleteado-109","sourceHandles":["972B0","97149","96C5A","9714A","9714B","9714C","9714D","9714E"]},{"partId":"tubo-aleteado-110","sourceHandles":["972AD","97143","96C58","97144","97145","97146","97147","97148"]},{"partId":"tubo-aleteado-111","sourceHandles":["972B1","971CC","96C65","971CD","971CE","971CF","971D0","971D1"]},{"partId":"tubo-aleteado-112","sourceHandles":["972AE","971D2","96C63","96C6A","971D3","971D4","971D5","971D6"]},{"partId":"tubo-aleteado-113","sourceHandles":["97334","96E63","96C68","96D2C","96E64","96E65","96E66","96E67","96E68","96E69","96E6A","96E6B"]},{"partId":"tubo-aleteado-114","sourceHandles":["97331","971C1","96D2A","96D59","971C2","971C3","971C4","971C5","971C6","971C7","971C8","971C9"]},{"partId":"tubo-aleteado-115","sourceHandles":["97335","96E6C","96D57","96D86","96E6D","96E6E","96E6F","96E70","96E71","96E72","96E73","96E74"]},{"partId":"tubo-aleteado-116","sourceHandles":["97332","96E75","96D84","96DB3","96E76","96E77","96E78","96E79","96E7A","96E7B","96E7C","96E7D"]},{"partId":"tubo-aleteado-117","sourceHandles":["97370","96E7E","96DB1","96DE0","96E7F","96E80","96E81","96E82","96E83","96E84","96E85","96E86"]},{"partId":"tubo-aleteado-118","sourceHandles":["9736D","96E87","96DDE","96E0D","96E88","96E89","96E8A","96E8B","96E8C","96E8D","96E8E","96E8F"]},{"partId":"tubo-aleteado-119","sourceHandles":["97371","96E90","96E0B","96E3A","96E91","96E92","96E93","96E94","96E95","96E96","96E97","96E98"]},{"partId":"tubo-aleteado-120","sourceHandles":["9736E","96E99","96E38","96E9A","96E9B","96E9C","96E9D","96E9E","96E9F","96EA0","96EA1","96EA2"]}],"actualExtentManufacturerAxesM":[2.824958,2.348964,11.5],"quantityUse":"Magnitudes de la geometría representada; no son cantidades de material, obra, compra, capacidad útil ni fabricación. En geometrías compuestas se suman superficies y volúmenes de partes y pueden existir solapes no depurados.","actualExtentScope":"Extensión del haz aleteado representado; el contorno general documentado de la máquina es 3,418 × 2,848 m.","issues":["El haz aleteado modelado mide aproximadamente 2,825 × 2,349 m en planta. El contorno general documentado de 3,418 × 2,848 m incluye elementos no detallados; no se sustituye por el tamaño del haz."]} | {"elementId":"LV1802B","ifcGuid":"3dJJeFbpPPgvjPEafe$hVT","ifcClass":"IfcHeatExchanger","buildingId":"process_plant","buildingName":"Planta de proceso","sourceDocumentId":"EQ-CARGAS-20260825","sourceRepresentationKind":"equipment"} | LV1802B | 44E | 2678 | {"documentId":"EQ-IMPLANTACION-20260430","title":"Plano del fabricante: implantación de equipos · referencia E7","sheet":"Espacio modelo; referencia E7 en el nombre del archivo","date":"2026-04-30","insertHandle":"8361F"} | {"min":[6.532,6.277,0],"max":[9.95,9.125,11.5]}
Vaporizador de nitrógeno líquido LV1802C | ["found_0904_fe1e9d7a392163","found_0904_4939b606bb2942","found_0904_4e3ba53c588b2c","found_0904_aa0c02564490dd","found_0904_253a35067636ca","found_0904_ebd95b663d3032","found_0904_c45eec1ff6ea2b","found_0904_064fa9b0b0b220","found_0904_16f158bd07b9be","found_0904_e0a9ebf030837d","found_0904_6b497236897623","found_0904_32c81642b7a681"] | {"documented":[{"label":"Dimensión X local del contorno CAD","value":3.418,"unit":"m","source":"EQ-CARGAS-20260825 · contorno CAD · handles 454","status":"derivado"},{"label":"Dimensión Y local del contorno CAD","value":2.848,"unit":"m","source":"EQ-CARGAS-20260825 · contorno CAD · handles 454","status":"derivado"},{"label":"Altura acotada","value":11.5,"unit":"m","source":"EQ-CARGAS-20260825 · handle 2686","status":"documentado"},{"label":"Cota relativa de la superficie de apoyo","value":0.515,"unit":"m","source":"LHD2609-JG00100-20260904 · sección 8 / 8-8 · 1FF47, 1FF4A, 1FF4D, 1FF50, 1FF58","status":"documentado"}],"geometry":[{"label":"Extensión de la malla en X","value":3.0949659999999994,"unit":"m","source":"Geometría releída del IFC; datum absoluto de proceso provisional","status":"derivado"},{"label":"Extensión de la malla en Y","value":2.68506,"unit":"m","source":"Geometría releída del IFC; datum absoluto de proceso provisional","status":"derivado"},{"label":"Extensión de la malla en Z","value":11.5,"unit":"m","source":"Geometría releída del IFC; datum absoluto de proceso provisional","status":"derivado"},{"label":"Cota inferior de visualización","value":286.615,"unit":"m","source":"Geometría releída del IFC; datum absoluto de proceso provisional","status":"derivado"},{"label":"Cota superior de visualización","value":298.115,"unit":"m","source":"Geometría releída del IFC; datum absoluto de proceso provisional","status":"derivado"}],"notes":["Las extensiones de la malla se miden en los ejes del proyecto tras el giro de implantación; no sustituyen las dimensiones locales del fabricante.","La envolvente, su volumen y los espesores de visualización no son volúmenes de material ni cantidades de compra, construcción o fabricación.","Las dimensiones documentadas distinguen cotas explícitas y medidas extraídas de contornos CAD; las dimensiones geométricas describen únicamente la malla publicada.","Las extensiones de la malla refinada y las dimensiones documentadas del contorno o bastidor tienen distinto alcance; las cotas parciales del detalle son provisionales."]} | {"boundingBoxM":{"min":[45.774195,34.410997,1.615],"max":[48.869161,37.096057,13.115]},"extentsM":[3.094966,2.68506,11.5],"meshSurfaceM2":2739.822228,"meshVolumeM3":4.150706,"closedSolid":true,"basis":"Magnitudes de las mallas representadas, no cantidades certificadas de obra, compra o fabricación. Las partes pueden compartir superficies; no se suman como un despiece de materiales."} | {"source":{"documentId":"EQ-IMPLANTACION-20260430","title":"Plano del fabricante: implantación de equipos · referencia E7","sheet":"Espacio modelo; referencia E7 en el nombre del archivo","date":"2026-04-30","insertHandle":"83620"},"revision":"Detalle de planta E7 2026-04-30; altura global 2026-08-25","horizontalStatus":"120 centros y trazos de aleta por unidad derivados directamente de los vectores CAD; perfil de espesor provisional.","verticalRule":"Extrusión conceptual continua entre z=0 y z=11,5 m respecto al fondo del equipo. No se asignan alturas inventadas a apoyos ni a bastidores.","status":"provisional","unconfirmedDimensions":["Espesor de aleta de 3 mm adoptado exclusivamente para visualización; no es un espesor de fabricación documentado.","Longitud activa de las aletas, separación al suelo, bastidor y altura de apoyos sin cotas verificadas.","La sección de planta se prolonga desde 0 hasta 11,5 m; la altura total está documentada, pero su distribución vertical es provisional.","Compatibilidad entre el detalle de planta de abril y las dimensiones generales de agosto pendiente de confirmación del fabricante."],"array":{"units":120,"columns":12,"rows":10,"finTraceCounts":{"6":16,"10":24,"8":24,"12":56}},"nominalVisualizationFinThicknessM":0.003,"documentedOverallHeightM":11.5,"referenceEnvelopePadM":{"min":[11.932,6.277,0],"max":[15.350000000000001,9.125,11.5]},"measurementBasis":"Geometría de visualización; no utilizar para peso, superficie de intercambio ni medición de suministro.","heightSource":{"documentId":"EQ-CARGAS-20260825","title":"Plano del fabricante: cargas de equipos","sheet":"Espacio modelo","date":"2026-08-25"},"partsAreBOM":false,"partCount":120,"sourcePartHandles":[{"partId":"tubo-aleteado-001","sourceHandles":["972E6","971B9","96CFA","971BA","971BB","971BC","971BD","971BE"]},{"partId":"tubo-aleteado-002","sourceHandles":["972E3","971B1","96CF8","971B2","971B3","971B5","971B7","971B8"]},{"partId":"tubo-aleteado-003","sourceHandles":["972E7","9723A","96D04","9723B","9723C","9723D","9723E","97240"]},{"partId":"tubo-aleteado-004","sourceHandles":["972E4","97241","96D02","96D09","97242","97243","97244","97245"]},{"partId":"tubo-aleteado-005","sourceHandles":["9736A","970F2","96D07","96D53","970F3","970F4","970F5","970F7","970F8","970FA","970FB","970FC"]},{"partId":"tubo-aleteado-006","sourceHandles":["97367","970FD","96D51","96D80","970FE","970FF","97100","97101","97102","97104","97105","97106"]},{"partId":"tubo-aleteado-007","sourceHandles":["9736B","97107","96D7E","96DAD","97108","97109","9710A","9710B","9710C","9710E","9710F","97110"]},{"partId":"tubo-aleteado-008","sourceHandles":["97368","97111","96DAB","96DDA","97112","97113","97114","97115","97116","97118","97119","9711A"]},{"partId":"tubo-aleteado-009","sourceHandles":["973A6","9711B","96DD8","96E07","9711C","9711D","9711E","9711F","97120","97122","97123","97124"]},{"partId":"tubo-aleteado-010","sourceHandles":["973A3","97125","96E05","96E34","97126","97127","97128","97129","9712A","9712C","9712D","9712E"]},{"partId":"tubo-aleteado-011","sourceHandles":["973A7","9712F","96E32","96E61","97130","97131","97132","97133","97134","97136","97137","97138"]},{"partId":"tubo-aleteado-012","sourceHandles":["973A4","97139","96E5F","9713A","9713B","9713C","9713D","9713E","9713F","97140","97141","97142"]},{"partId":"tubo-aleteado-013","sourceHandles":["972E0","971AC","96CE6","96CFB","971AD","971AE","971AF","971B0"]},{"partId":"tubo-aleteado-014","sourceHandles":["972DD","971A5","96CE4","96CF9","971A6","971A7","971A8","971A9","971AA","971AB"]},{"partId":"tubo-aleteado-015","sourceHandles":["972E1","9722E","96CF0","96D05","9722F","97230","97231","97232","97233","97234"]},{"partId":"tubo-aleteado-016","sourceHandles":["972DE","97235","96CEE","96CF5","96D03","96D0A","97236","97237","97238","97239"]},{"partId":"tubo-aleteado-017","sourceHandles":["97364","970AA","96CF3","96D08","96D4E","96D54","970AB","970AC","970AD","970AE","970AF","970B0","970B1","970B2"]},{"partId":"tubo-aleteado-018","sourceHandles":["97361","970B3","96D4C","96D52","96D7B","96D81","970B4","970B5","970B6","970B7","970B8","970B9","970BA","970BB"]},{"partId":"tubo-aleteado-019","sourceHandles":["97365","970BC","96D79","96D7F","96DA8","96DAE","970BD","970BE","970BF","970C0","970C1","970C2","970C3","970C4"]},{"partId":"tubo-aleteado-020","sourceHandles":["97362","970C5","96DA6","96DAC","96DD5","96DDB","970C6","970C7","970C8","970C9","970CA","970CB","970CC","970CD"]},{"partId":"tubo-aleteado-021","sourceHandles":["973A0","970CE","96DD3","96DD9","96E02","96E08","970CF","970D0","970D1","970D2","970D3","970D4","970D5","970D6"]},{"partId":"tubo-aleteado-022","sourceHandles":["9739D","970D7","96E00","96E06","96E2F","96E35","970D8","970D9","970DA","970DB","970DC","970DD","970DE","970DF"]},{"partId":"tubo-aleteado-023","sourceHandles":["973A1","970E0","96E2D","96E33","96E5C","96E62","970E1","970E2","970E3","970E4","970E5","970E6","970E7","970E8"]},{"partId":"tubo-aleteado-024","sourceHandles":["9739E","970E9","96E5A","96E60","970EA","970EB","970EC","970ED","970EE","970EF","970F0","970F1"]},{"partId":"tubo-aleteado-025","sourceHandles":["972DA","971A0","96CD2","96CE7","971A1","971A2","971A3","971A4"]},{"partId":"tubo-aleteado-026","sourceHandles":["972D7","97199","96CD0","96CE5","9719A","9719B","9719C","9719D","9719E","9719F"]},{"partId":"tubo-aleteado-027","sourceHandles":["972DB","97222","96CDC","96CF1","97223","97224","97225","97226","97227","97228"]},{"partId":"tubo-aleteado-028","sourceHandles":["972D8","97229","96CDA","96CE1","96CEF","96CF6","9722A","9722B","9722C","9722D"]},{"partId":"tubo-aleteado-029","sourceHandles":["9735E","97062","96CDF","96CF4","96D49","96D4F","97063","97064","97065","97066","97067","97068","97069","9706A"]},{"partId":"tubo-aleteado-030","sourceHandles":["9735B","9706B","96D47","96D4D","96D76","96D7C","9706C","9706D","9706E","9706F","97070","97071","97072","97073"]},{"partId":"tubo-aleteado-031","sourceHandles":["9735F","97074","96D74","96D7A","96DA3","96DA9","97075","97076","97077","97078","97079","9707A","9707B","9707C"]},{"partId":"tubo-aleteado-032","sourceHandles":["9735C","9707D","96DA1","96DA7","96DD0","96DD6","9707E","9707F","97080","97081","97082","97083","97084","97085"]},{"partId":"tubo-aleteado-033","sourceHandles":["9739A","97086","96DCE","96DD4","96DFD","96E03","97087","97088","97089","9708A","9708B","9708C","9708D","9708E"]},{"partId":"tubo-aleteado-034","sourceHandles":["97397","9708F","96DFB","96E01","96E2A","96E30","97090","97091","97092","97093","97094","97095","97096","97097"]},{"partId":"tubo-aleteado-035","sourceHandles":["9739B","97098","96E28","96E2E","96E57","96E5D","97099","9709A","9709B","9709C","9709D","9709E","9709F","970A0"]},{"partId":"tubo-aleteado-036","sourceHandles":["97398","970A1","96E55","96E5B","970A2","970A3","970A4","970A5","970A6","970A7","970A8","970A9"]},{"partId":"tubo-aleteado-037","sourceHandles":["972D4","97194","96CBE","96CD3","97195","97196","97197","97198"]},{"partId":"tubo-aleteado-038","sourceHandles":["972D1","9718D","96CBC","96CD1","9718E","9718F","97190","97191","97192","97193"]},{"partId":"tubo-aleteado-039","sourceHandles":["972D5","97216","96CC8","96CDD","97217","97218","97219","9721A","9721B","9721C"]},{"partId":"tubo-aleteado-040","sourceHandles":["972D2","9721D","96CC6","96CCD","96CDB","96CE2","9721E","9721F","97220","97221"]},{"partId":"tubo-aleteado-041","sourceHandles":["97358","9701A","96CCB","96CE0","96D44","96D4A","9701B","9701C","9701D","9701E","9701F","97020","97021","97022"]},{"partId":"tubo-aleteado-042","sourceHandles":["97355","97023","96D42","96D48","96D71","96D77","97024","97025","97026","97027","97028","97029","9702A","9702B"]},{"partId":"tubo-aleteado-043","sourceHandles":["97359","9702C","96D6F","96D75","96D9E","96DA4","9702D","9702E","9702F","97030","97031","97032","97033","97034"]},{"partId":"tubo-aleteado-044","sourceHandles":["97356","97035","96D9C","96DA2","96DCB","96DD1","97036","97037","97038","97039","9703A","9703B","9703C","9703D"]},{"partId":"tubo-aleteado-045","sourceHandles":["97394","9703E","96DC9","96DCF","96DF8","96DFE","9703F","97040","97041","97042","97043","97044","97045","97046"]},{"partId":"tubo-aleteado-046","sourceHandles":["97391","97047","96DF6","96DFC","96E25","96E2B","97048","97049","9704A","9704B","9704C","9704D","9704E","9704F"]},{"partId":"tubo-aleteado-047","sourceHandles":["97395","97050","96E23","96E29","96E52","96E58","97051","97052","97053","97054","97055","97056","97057","97058"]},{"partId":"tubo-aleteado-048","sourceHandles":["97392","97059","96E50","96E56","9705A","9705B","9705C","9705D","9705E","9705F","97060","97061"]},{"partId":"tubo-aleteado-049","sourceHandles":["972CE","97188","96CAA","96CBF","97189","9718A","9718B","9718C"]},{"partId":"tubo-aleteado-050","sourceHandles":["972CB","97181","96CA8","96CBD","97182","97183","97184","97185","97186","97187"]},{"partId":"tubo-aleteado-051","sourceHandles":["972CF","9720A","96CB4","96CC9","9720B","9720C","9720D","9720E","9720F","97210"]},{"partId":"tubo-aleteado-052","sourceHandles":["972CC","97211","96CB2","96CB9","96CC7","96CCE","97212","97213","97214","97215"]},{"partId":"tubo-aleteado-053","sourceHandles":["97352","96FD2","96CB7","96CCC","96D3F","96D45","96FD3","96FD4","96FD5","96FD6","96FD7","96FD8","96FD9","96FDA"]},{"partId":"tubo-aleteado-054","sourceHandles":["9734F","96FDB","96D3D","96D43","96D6C","96D72","96FDC","96FDD","96FDE","96FDF","96FE0","96FE1","96FE2","96FE3"]},{"partId":"tubo-aleteado-055","sourceHandles":["97353","96FE4","96D6A","96D70","96D99","96D9F","96FE5","96FE6","96FE7","96FE8","96FE9","96FEA","96FEB","96FEC"]},{"partId":"tubo-aleteado-056","sourceHandles":["97350","96FED","96D97","96D9D","96DC6","96DCC","96FEE","96FEF","96FF0","96FF1","96FF2","96FF3","96FF4","96FF5"]},{"partId":"tubo-aleteado-057","sourceHandles":["9738E","96FF6","96DC4","96DCA","96DF3","96DF9","96FF7","96FF8","96FF9","96FFA","96FFB","96FFC","96FFD","96FFE"]},{"partId":"tubo-aleteado-058","sourceHandles":["9738B","96FFF","96DF1","96DF7","96E20","96E26","97000","97001","97002","97003","97004","97005","97006","97007"]},{"partId":"tubo-aleteado-059","sourceHandles":["9738F","97008","96E1E","96E24","96E4D","96E53","97009","9700A","9700B","9700C","9700D","9700E","9700F","97010"]},{"partId":"tubo-aleteado-060","sourceHandles":["9738C","97011","96E4B","96E51","97012","97013","97014","97015","97016","97017","97018","97019"]},{"partId":"tubo-aleteado-061","sourceHandles":["972C8","9717C","96C96","96CAB","9717D","9717E","9717F","97180"]},{"partId":"tubo-aleteado-062","sourceHandles":["972C5","97175","96C94","96CA9","97176","97177","97178","97179","9717A","9717B"]},{"partId":"tubo-aleteado-063","sourceHandles":["972C9","971FE","96CA0","96CB5","971FF","97200","97201","97202","97203","97204"]},{"partId":"tubo-aleteado-064","sourceHandles":["972C6","97205","96C9E","96CA5","96CB3","96CBA","97206","97207","97208","97209"]},{"partId":"tubo-aleteado-065","sourceHandles":["9734C","96F8A","96CA3","96CB8","96D3A","96D40","96F8B","96F8C","96F8D","96F8E","96F8F","96F90","96F91","96F92"]},{"partId":"tubo-aleteado-066","sourceHandles":["97349","96F93","96D38","96D3E","96D67","96D6D","96F94","96F95","96F96","96F97","96F98","96F99","96F9A","96F9B"]},{"partId":"tubo-aleteado-067","sourceHandles":["9734D","96F9C","96D65","96D6B","96D94","96D9A","96F9D","96F9E","96F9F","96FA0","96FA1","96FA2","96FA3","96FA4"]},{"partId":"tubo-aleteado-068","sourceHandles":["9734A","96FA5","96D92","96D98","96DC1","96DC7","96FA6","96FA7","96FA8","96FA9","96FAA","96FAB","96FAC","96FAD"]},{"partId":"tubo-aleteado-069","sourceHandles":["97388","96FAE","96DBF","96DC5","96DEE","96DF4","96FAF","96FB0","96FB1","96FB2","96FB3","96FB4","96FB5","96FB6"]},{"partId":"tubo-aleteado-070","sourceHandles":["97385","96FB7","96DEC","96DF2","96E1B","96E21","96FB8","96FB9","96FBA","96FBB","96FBC","96FBD","96FBE","96FBF"]},{"partId":"tubo-aleteado-071","sourceHandles":["97389","96FC0","96E19","96E1F","96E48","96E4E","96FC1","96FC2","96FC3","96FC4","96FC5","96FC6","96FC7","96FC8"]},{"partId":"tubo-aleteado-072","sourceHandles":["97386","96FC9","96E46","96E4C","96FCA","96FCB","96FCC","96FCD","96FCE","96FCF","96FD0","96FD1"]},{"partId":"tubo-aleteado-073","sourceHandles":["972C2","97170","96C82","96C97","97171","97172","97173","97174"]},{"partId":"tubo-aleteado-074","sourceHandles":["972BF","97169","96C80","96C95","9716A","9716B","9716C","9716D","9716E","9716F"]},{"partId":"tubo-aleteado-075","sourceHandles":["972C3","971F2","96C8C","96CA1","971F3","971F4","971F5","971F6","971F7","971F8"]},{"partId":"tubo-aleteado-076","sourceHandles":["972C0","971F9","96C8A","96C91","96C9F","96CA6","971FA","971FB","971FC","971FD"]},{"partId":"tubo-aleteado-077","sourceHandles":["97346","96F42","96C8F","96CA4","96D35","96D3B","96F43","96F44","96F45","96F46","96F47","96F48","96F49","96F4A"]},{"partId":"tubo-aleteado-078","sourceHandles":["97343","96F4B","96D33","96D39","96D62","96D68","96F4C","96F4D","96F4E","96F4F","96F50","96F51","96F52","96F53"]},{"partId":"tubo-aleteado-079","sourceHandles":["97347","96F54","96D60","96D66","96D8F","96D95","96F55","96F56","96F57","96F58","96F59","96F5A","96F5B","96F5C"]},{"partId":"tubo-aleteado-080","sourceHandles":["97344","96F5D","96D8D","96D93","96DBC","96DC2","96F5E","96F5F","96F60","96F61","96F62","96F63","96F64","96F65"]},{"partId":"tubo-aleteado-081","sourceHandles":["97382","96F66","96DBA","96DC0","96DE9","96DEF","96F67","96F68","96F69","96F6A","96F6B","96F6C","96F6D","96F6E"]},{"partId":"tubo-aleteado-082","sourceHandles":["9737F","96F6F","96DE7","96DED","96E16","96E1C","96F70","96F71","96F72","96F73","96F74","96F75","96F76","96F77"]},{"partId":"tubo-aleteado-083","sourceHandles":["97383","96F78","96E14","96E1A","96E43","96E49","96F79","96F7A","96F7B","96F7C","96F7D","96F7E","96F7F","96F80"]},{"partId":"tubo-aleteado-084","sourceHandles":["97380","96F81","96E41","96E47","96F82","96F83","96F84","96F85","96F86","96F87","96F88","96F89"]},{"partId":"tubo-aleteado-085","sourceHandles":["972BC","97164","96C6E","96C83","97165","97166","97167","97168"]},{"partId":"tubo-aleteado-086","sourceHandles":["972B9","9715D","96C6C","96C81","9715E","9715F","97160","97161","97162","97163"]},{"partId":"tubo-aleteado-087","sourceHandles":["972BD","971E6","96C78","96C8D","971E7","971E8","971E9","971EA","971EB","971EC"]},{"partId":"tubo-aleteado-088","sourceHandles":["972BA","971ED","96C76","96C7D","96C8B","96C92","971EE","971EF","971F0","971F1"]},{"partId":"tubo-aleteado-089","sourceHandles":["97340","96EFA","96C7B","96C90","96D30","96D36","96EFB","96EFC","96EFD","96EFE","96EFF","96F00","96F01","96F02"]},{"partId":"tubo-aleteado-090","sourceHandles":["9733D","96F03","96D2E","96D34","96D5D","96D63","96F04","96F05","96F06","96F07","96F08","96F09","96F0A","96F0B"]},{"partId":"tubo-aleteado-091","sourceHandles":["97341","96F0C","96D5B","96D61","96D8A","96D90","96F0D","96F0E","96F0F","96F10","96F11","96F12","96F13","96F14"]},{"partId":"tubo-aleteado-092","sourceHandles":["9733E","96F15","96D88","96D8E","96DB7","96DBD","96F16","96F17","96F18","96F19","96F1A","96F1B","96F1C","96F1D"]},{"partId":"tubo-aleteado-093","sourceHandles":["9737C","96F1E","96DB5","96DBB","96DE4","96DEA","96F1F","96F20","96F21","96F22","96F23","96F24","96F25","96F26"]},{"partId":"tubo-aleteado-094","sourceHandles":["97379","96F27","96DE2","96DE8","96E11","96E17","96F28","96F29","96F2A","96F2B","96F2C","96F2D","96F2E","96F2F"]},{"partId":"tubo-aleteado-095","sourceHandles":["9737D","96F30","96E0F","96E15","96E3E","96E44","96F31","96F32","96F33","96F34","96F35","96F36","96F37","96F38"]},{"partId":"tubo-aleteado-096","sourceHandles":["9737A","96F39","96E3C","96E42","96F3A","96F3B","96F3C","96F3D","96F3E","96F3F","96F40","96F41"]},{"partId":"tubo-aleteado-097","sourceHandles":["972B6","97157","96C6F","97158","97159","9715A","9715B","9715C"]},{"partId":"tubo-aleteado-098","sourceHandles":["972B3","9714F","96C6D","97150","97151","97152","97153","97154","97155","97156"]},{"partId":"tubo-aleteado-099","sourceHandles":["972B7","971D7","96C79","971D8","971D9","971DA","971DB","971DC","971DD","971DE"]},{"partId":"tubo-aleteado-100","sourceHandles":["972B4","971DF","96C77","96C7E","971E0","971E1","971E2","971E3","971E4","971E5"]},{"partId":"tubo-aleteado-101","sourceHandles":["9733A","96EA3","96C7C","96D31","96EA4","96EA5","96EA6","96EA7","96EA8","96EA9","96EAA","96EAB","96EAC","96EAD"]},{"partId":"tubo-aleteado-102","sourceHandles":["97337","96EAE","96D2F","96D5E","96EAF","96EB0","96EB1","96EB2","96EB3","96EB4","96EB5","96EB6","96EB7","96EB8"]},{"partId":"tubo-aleteado-103","sourceHandles":["9733B","96EB9","96D5C","96D8B","96EBA","96EBB","96EBC","96EBD","96EBE","96EBF","96EC0","96EC1","96EC2","96EC3"]},{"partId":"tubo-aleteado-104","sourceHandles":["97338","96EC4","96D89","96DB8","96EC5","96EC6","96EC7","96EC8","96EC9","96ECA","96ECB","96ECC","96ECD","96ECE"]},{"partId":"tubo-aleteado-105","sourceHandles":["97376","96ECF","96DB6","96DE5","96ED0","96ED1","96ED2","96ED3","96ED4","96ED5","96ED6","96ED7","96ED8","96ED9"]},{"partId":"tubo-aleteado-106","sourceHandles":["97373","96EDA","96DE3","96E12","96EDB","96EDC","96EDD","96EDE","96EDF","96EE0","96EE1","96EE2","96EE3","96EE4"]},{"partId":"tubo-aleteado-107","sourceHandles":["97377","96EE5","96E10","96E3F","96EE6","96EE7","96EE8","96EE9","96EEA","96EEB","96EEC","96EED","96EEE","96EEF"]},{"partId":"tubo-aleteado-108","sourceHandles":["97374","96EF0","96E3D","96EF1","96EF2","96EF3","96EF4","96EF5","96EF6","96EF7","96EF8","96EF9"]},{"partId":"tubo-aleteado-109","sourceHandles":["972B0","97149","96C5A","9714A","9714B","9714C","9714D","9714E"]},{"partId":"tubo-aleteado-110","sourceHandles":["972AD","97143","96C58","97144","97145","97146","97147","97148"]},{"partId":"tubo-aleteado-111","sourceHandles":["972B1","971CC","96C65","971CD","971CE","971CF","971D0","971D1"]},{"partId":"tubo-aleteado-112","sourceHandles":["972AE","971D2","96C63","96C6A","971D3","971D4","971D5","971D6"]},{"partId":"tubo-aleteado-113","sourceHandles":["97334","96E63","96C68","96D2C","96E64","96E65","96E66","96E67","96E68","96E69","96E6A","96E6B"]},{"partId":"tubo-aleteado-114","sourceHandles":["97331","971C1","96D2A","96D59","971C2","971C3","971C4","971C5","971C6","971C7","971C8","971C9"]},{"partId":"tubo-aleteado-115","sourceHandles":["97335","96E6C","96D57","96D86","96E6D","96E6E","96E6F","96E70","96E71","96E72","96E73","96E74"]},{"partId":"tubo-aleteado-116","sourceHandles":["97332","96E75","96D84","96DB3","96E76","96E77","96E78","96E79","96E7A","96E7B","96E7C","96E7D"]},{"partId":"tubo-aleteado-117","sourceHandles":["97370","96E7E","96DB1","96DE0","96E7F","96E80","96E81","96E82","96E83","96E84","96E85","96E86"]},{"partId":"tubo-aleteado-118","sourceHandles":["9736D","96E87","96DDE","96E0D","96E88","96E89","96E8A","96E8B","96E8C","96E8D","96E8E","96E8F"]},{"partId":"tubo-aleteado-119","sourceHandles":["97371","96E90","96E0B","96E3A","96E91","96E92","96E93","96E94","96E95","96E96","96E97","96E98"]},{"partId":"tubo-aleteado-120","sourceHandles":["9736E","96E99","96E38","96E9A","96E9B","96E9C","96E9D","96E9E","96E9F","96EA0","96EA1","96EA2"]}],"actualExtentManufacturerAxesM":[2.824958,2.348964,11.5],"quantityUse":"Magnitudes de la geometría representada; no son cantidades de material, obra, compra, capacidad útil ni fabricación. En geometrías compuestas se suman superficies y volúmenes de partes y pueden existir solapes no depurados.","actualExtentScope":"Extensión del haz aleteado representado; el contorno general documentado de la máquina es 3,418 × 2,848 m.","issues":["El haz aleteado modelado mide aproximadamente 2,825 × 2,349 m en planta. El contorno general documentado de 3,418 × 2,848 m incluye elementos no detallados; no se sustituye por el tamaño del haz."]} | {"elementId":"LV1802C","ifcGuid":"0dnENMUGvQ5hbejy5HmMTM","ifcClass":"IfcHeatExchanger","buildingId":"process_plant","buildingName":"Planta de proceso","sourceDocumentId":"EQ-CARGAS-20260825","sourceRepresentationKind":"equipment"} | LV1802C | 454 | 2686 | {"documentId":"EQ-IMPLANTACION-20260430","title":"Plano del fabricante: implantación de equipos · referencia E7","sheet":"Espacio modelo; referencia E7 en el nombre del archivo","date":"2026-04-30","insertHandle":"83620"} | {"min":[11.932,6.277,0],"max":[15.350000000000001,9.125,11.5]}

# IfcHeatExchanger: Marcador de equipo en planta (2)
In: Parcela industrial Jinhong
Description: Equipo industrial; PredefinedType: USERDEFINED; Document: Plano del fabricante: cargas de equipos; Plano del fabricante: implantación de equipos · referencia E7; Cimentaciones de equipos y pedestales del fabricante · revisión recibida 04/09/2026; Group: Equipos; Zona de separación de aire; BIM · Equipos
JH_DimensionesDelModelo - Extensión de la malla en X: 0.793126 m; Extensión de la malla en Y: 2.97799 m; Extensión de la malla en Z: 0.45 m; Cota inferior de visualización: 286.575 m; Cota superior de visualización: 287.025 m
JH_MagnitudesGeometricas - ExtensionX: 0.793126 m; ExtensionY: 2.97799 m; ExtensionZ: 0.45 m; SuperficieDeLaMalla: 4.43952 m2; VolumenGeometrico: 0.25246 m3
JH_CoordinacionCimentaciones - Relacion: Correspondencia documental; no verifica anclajes ni cotas de montaje.
JH_InformacionBIM - buildingId: process_plant; buildingName: Planta de proceso; level: Apoyo relativo +0.200 m; cero absoluto provisional; category: Equipo industrial; ifcClass: IfcHeatExchanger; representationKind: equipment; material: {"name":"No especificado","source":"Los contornos revisados no especifican el material del equipo.","status":"unknown"}; dimensions: {"documented":[{"label":"Diámetro exterior del cuerpo","value":0.3239,"unit":"m","source":"EQ-IMPLANTACION-20260430 · líneas 9E9B7 y 9E9BD","status":"derivado"},{"label":"Longitud total entre extremos","value":3.006,"unit":"m","source":"EQ-IMPLANTACION-20260430 · extremos del perfil 9E9AA y 9E9B2","status":"derivado"},{"label":"Diámetro exterior de las cuatro bridas axiales","value":0.45,"unit":"m","source":"EQ-IMPLANTACION-20260430 · contornos 9E9C3–9E9D3","status":"derivado"},{"label":"Espesor axial de cada brida","value":0.045,"unit":"m","source":"EQ-IMPLANTACION-20260430 · contornos 9E9C3–9E9D3","status":"derivado"},{"label":"Cota relativa de la superficie de apoyo","value":0.2,"unit":"m","source":"LHD2609-JG00100-20260904 · sección 6 / 6-6 · 28D77, 28D7A, 28DB3","status":"documentado"}],"geometry":[{"label":"Extensión de la malla en X","value":0.7931263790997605,"unit":"m","source":"Geometría releída del IFC; datum absoluto de proceso provisional","status":"derivado"},{"label":"Extensión de la malla en Y","value":2.9779865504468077,"unit":"m","source":"Geometría releída del IFC; datum absoluto de proceso provisional","status":"derivado"},{"label":"Extensión de la malla en Z","value":0.4500000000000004,"unit":"m","source":"Geometría releída del IFC; datum absoluto de proceso provisional","status":"derivado"},{"label":"Cota inferior de visualización","value":286.57500000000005,"unit":"m","source":"Geometría releída del IFC; datum absoluto de proceso provisional","status":"derivado"},{"label":"Cota superior de visualización","value":287.02500000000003,"unit":"m","source":"Geometría releída del IFC; datum absoluto de proceso provisional","status":"derivado"}],"notes":["Geometría exterior de referencia; los volúmenes no representan cantidades de material, compra o fabricación.","Cota del eje adoptada provisionalmente: +0,50 m respecto al plano de apoyo, separada de las dimensiones documentadas."]}; source: {"documentId":"EQ-IMPLANTACION-20260430","title":"Plano del fabricante: implantación de equipos · referencia E7","sheet":"Espacio modelo; referencia E7 en el nombre del archivo","date":"2026-04-30"}; status: provisional; positioning: {"Estado de la planta":"Derivado del CAD y del giro de implantación","Nivel relativo del apoyo (m)":0.2,"Estado del nivel relativo":"Documentado en el plano de cimentaciones","Cero absoluto de visualización (m)":286.1,"Estado del cero absoluto":"Provisional","Cota del apoyo de visualización (m)":286.3,"Desplazamiento aplicado a la malla (m)":0.2,"Criterio":"Nivel de apoyo relativo documentado. Se adopta el cero de proceso a 286,10 m solo para visualización; la equivalencia absoluta no está confirmada. No se añade un espesor de montaje sin cota del fabricante. El eje del posenfriador mantiene su separación provisional respecto al apoyo; faltan las cotas de las cunas."}; issues: ["Cuerpo horizontal reconstruido por revolución del perfil axial del fabricante, con los extremos segmentados originales y cuatro bridas axiales.","La altura de los soportes y la cota del eje no están documentadas. Se adopta exclusivamente para visualización un eje a 0,50 m sobre el plano de apoyo; las bridas quedan a 0,275 m de este plano.","No se modelan soportes ni conexiones cuya altura no está documentada; los círculos de conexiones en planta no determinan su longitud vertical.","El modelo es una envolvente maciza de referencia; no representa espesores de pared, chapas, pernos ni componentes internos.","Dos pedestales DZ6 por posenfriador, grout de 50 mm termina en +0,200; cota -2,200 de planta contradice -2,000 del fondo de sección.","El cero absoluto de la revisión no está definido; 286,10 m sigue siendo una hipótesis de coordinación."]; installationSource: {"documentId":"LHD2609-JG00100-20260904","title":"Cimentaciones y pedestales de equipos · revisión recibida 04/09/2026","date":"2026-09-04","sheet":"6 / 6-6","sourceHandles":["28D77","28D7A","28DB3"]}; visualLayer: {"id":"equipment","name":"Equipos"}; materialAppearance: {"profileId":"equipment_silver","name":"Intercambiador · metal gris provisional","materialName":"No especificado","physicalMaterialStatus":"unknown","physicalMaterialSource":"Los contornos revisados no especifican el material del equipo.","appearanceStatus":"provisional","appearanceBasis":"Referencia visual de fotografías públicas de Jinhong Gas / fabricante. Apariencia provisional para coordinación; fotografías oficiales pueden orientar el color, pero no acreditan el material, el acabado ni el equipo concreto.","note":"La apariencia gráfica no modifica ni confirma la especificación física del material."}; componentSeparation: {"status":"envolvente_del_equipo_sin_interiores","note":"La malla representa el equipo completo o su envolvente. No existe una carcasa separada de los componentes internos."}; classification: {"layerId":"equipment","layerName":"Equipos","role":"Equipo industrial","basis":"Clasificación por función del elemento; no modifica las especificaciones documentales."}; layerId: equipment; appearance: {"profileId":"equipment_silver","name":"Intercambiador · metal gris provisional","status":"provisional","basis":"Referencia visual de fotografías públicas de Jinhong Gas / fabricante. Apariencia provisional para coordinación; fotografías oficiales pueden orientar el color, pero no acreditan el material, el acabado ni el equipo concreto.","physicalMaterialUnchanged":true}
JH_Trazabilidad - Disciplina: Equipos; Clase IFC: IfcHeatExchanger; Material: No especificado; Estado de la información: provisional; Aplicabilidad a mediciones: Geometría exterior de referencia; los volúmenes no representan cantidades de material, compra o fabricación.; Documento de origen: Plano del fabricante: implantación de equipos · referencia E7; Convención de coordenadas: Metros en la plataforma local del fabricante; transformación de implantación aplicada durante la integración.; Grado de definición: Cuerpo horizontal reconstruido por revolución del perfil axial del fabricante, con los extremos segmentados originales y cuatro bridas axiales.; La altura de los soportes y la cota del eje no están documentadas. Se adopta exclusivamente para visualización un eje a 0,50 m sobre el plano de apoyo; las bridas quedan a 0,275 m de este plano.; No se modelan soportes ni conexiones cuya altura no está documentada; los círculos de conexiones en planta no determinan su longitud vertical.; El modelo es una envolvente maciza de referencia; no representa espesores de pared, chapas, pernos ni componentes internos.; Identificadores CAD del contorno (handles): 9E9B7, 9E9BA, 9E9BD, 9E9C0, 9E9A7, 9E9A8, 9E9A9, 9E9AA, 9E9AF, 9E9B0, 9E9B1, 9E9B2, 9E9CB, 9E9CF, 9E9C3, 9E9C8; Nivel relativo de apoyo documentado (m): 0.2; Fuente del nivel de apoyo: {"documentId":"LHD2609-JG00100-20260904","title":"Cimentaciones y pedestales de equipos · revisión recibida 04/09/2026","date":"2026-09-04","sheet":"6 / 6-6","sourceHandles":["28D77","28D7A","28DB3"]}; Criterio de instalación: Nivel de apoyo relativo documentado. Se adopta el cero de proceso a 286,10 m solo para visualización; la equivalencia absoluta no está confirmada. No se añade un espesor de montaje sin cota del fabricante. El eje del posenfriador mantiene su separación provisional respecto al apoyo; faltan las cotas de las cunas.; Fase del modelo: Revisión de la zona de separación de aire · septiembre de 2026; Capa BIM: Equipos; Acabado de visualización: Intercambiador · metal gris provisional; Estado del acabado: provisional; Categoria: Equipo industrial; ClaseIFC: IfcHeatExchanger; EstadoDeInformacion: provisional; DocumentoFuente: {"documentId":"EQ-IMPLANTACION-20260430","title":"Plano del fabricante: implantación de equipos · referencia E7","sheet":"Espacio modelo; referencia E7 en el nombre del archivo","date":"2026-04-30"}; IncidenciasPendientes: ["Cuerpo horizontal reconstruido por revolución del perfil axial del fabricante, con los extremos segmentados originales y cuatro bridas axiales.","La altura de los soportes y la cota del eje no están documentadas. Se adopta exclusivamente para visualización un eje a 0,50 m sobre el plano de apoyo; las bridas quedan a 0,275 m de este plano.","No se modelan soportes ni conexiones cuya altura no está documentada; los círculos de conexiones en planta no determinan su longitud vertical.","El modelo es una envolvente maciza de referencia; no representa espesores de pared, chapas, pernos ni componentes internos.","Dos pedestales DZ6 por posenfriador, grout de 50 mm termina en +0,200; cota -2,200 de planta contradice -2,000 del fondo de sección.","El cero absoluto de la revisión no está definido; 286,10 m sigue siendo una hipótesis de coordinación."]; UsoDeLasMagnitudes: Geometría de coordinación. Los volúmenes de referencia y subcomponentes no son cantidades de material ni componentes de fabricación certificados.
JH_CriterioDePosicion - PosicionYEstado: {"Estado de la planta":"Derivado del CAD y del giro de implantación","Nivel relativo del apoyo (m)":0.2,"Estado del nivel relativo":"Documentado en el plano de cimentaciones","Cero absoluto de visualización (m)":286.1,"Estado del cero absoluto":"Provisional","Cota del apoyo de visualización (m)":286.3,"Desplazamiento aplicado a la malla (m)":0.2,"Criterio":"Nivel de apoyo relativo documentado. Se adopta el cero de proceso a 286,10 m solo para visualización; la equivalencia absoluta no está confirmada. No se añade un espesor de montaje sin cota del fabricante. El eje del posenfriador mantiene su separación provisional respecto al apoyo; faltan las cotas de las cunas."}
JH_EvidenciaDeMaterial - name: No especificado; source: Los contornos revisados no especifican el material del equipo.; status: unknown
JH_DimensionesDocumentadas - Diámetro exterior del cuerpo: 0.3239 m; Longitud total entre extremos: 3.006 m; Diámetro exterior de las cuatro bridas axiales: 0.45 m; Espesor axial de cada brida: 0.045 m; Cota relativa de la superficie de apoyo: 0.2 m
JH_DetalleGeometrico - source: {"documentId":"EQ-IMPLANTACION-20260430","title":"Plano del fabricante: implantación de equipos · referencia E7","sheet":"Espacio modelo; referencia E7 en el nombre del archivo","date":"2026-04-30"}; cadSource: equipment_layout.dxf; conversion: ODA; limitations: ["Cuerpo horizontal reconstruido por revolución del perfil axial del fabricante, con los extremos segmentados originales y cuatro bridas axiales.","La altura de los soportes y la cota del eje no están documentadas. Se adopta exclusivamente para visualización un eje a 0,50 m sobre el plano de apoyo; las bridas quedan a 0,275 m de este plano.","No se modelan soportes ni conexiones cuya altura no está documentada; los círculos de conexiones en planta no determinan su longitud vertical.","El modelo es una envolvente maciza de referencia; no representa espesores de pared, chapas, pernos ni componentes internos."]; shape: Revolución de perfil axial con fondos segmentados y cuatro bridas; unmodeledFeatures: ["Soportes: altura no documentada","Boquillas: longitud y elevación no documentadas","Pernos, espesores e interiores: no documentados"]
JH_CapaBIM - IdentificadorCapa: equipment; NombreCapa: Equipos; Funcion: Equipo industrial; VisibilidadInicial: yes
JH_AcabadoVisual - Perfil: equipment_silver; Acabado: Intercambiador · metal gris provisional; ColorRGB: [0.68,0.72,0.75]; Rugosidad: 0.38; Metallicidad: 0.7; Estado: provisional; Referencia: Referencia visual de fotografías públicas de Jinhong Gas / fabricante. Apariencia provisional para coordinación; fotografías oficiales pueden orientar el color, pero no acreditan el material, el acabado ni el equipo concreto.; Nota: La apariencia no certifica el material físico ni el acabado de fabricación.
Name | Reference = Identificador del objeto = Identificador | ElementosDeCimentacion = foundationIds | detailGeometry | geometryMetrics | visualizationIdentity | sourceInsertHandle
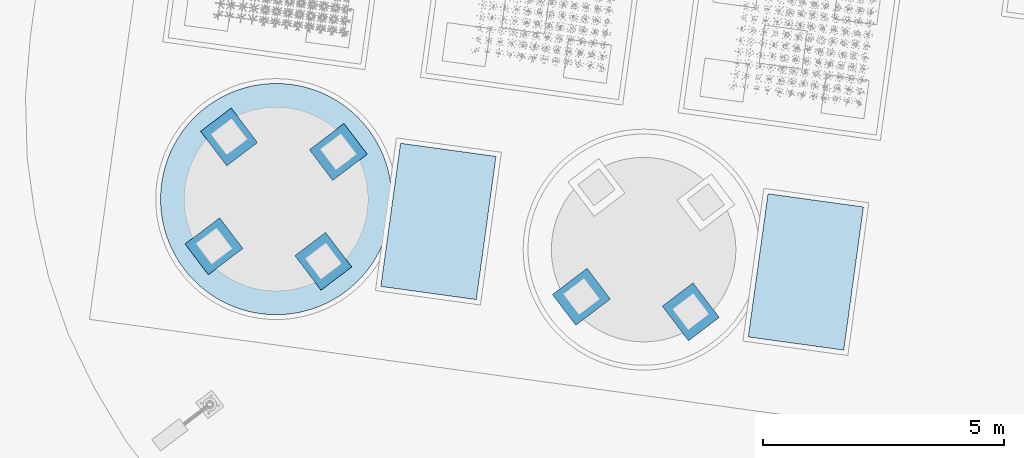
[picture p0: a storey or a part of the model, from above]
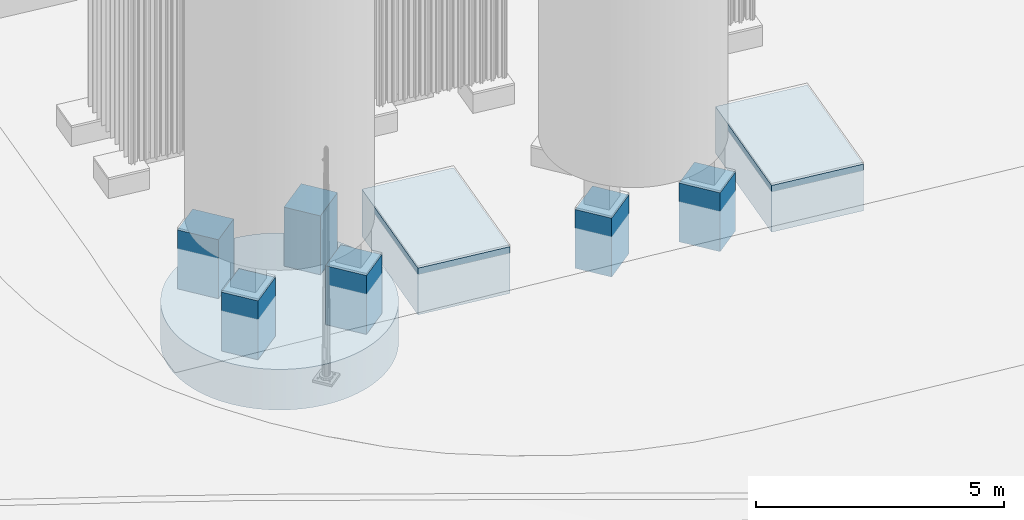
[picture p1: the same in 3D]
Properties of the parts of a building model (IFC4), part 90 of 134

# IfcHeatExchanger: Marcador de equipo en planta (2)
Name | Reference = Identificador del objeto = Identificador | ElementosDeCimentacion = foundationIds | detailGeometry | geometryMetrics | visualizationIdentity | sourceInsertHandle
Posenfriador horizontal WE441 · cuerpo, fondos y bridas | WE441-PLAN | ["found_0904_8f5d425169405d","found_0904_c9340bf51f56b7","found_0904_bca3cc43b8eae3","found_0904_6ce123701091e4","found_0904_cff6b400f13210","found_0904_e1d719443855d4"] | {"source":{"documentId":"EQ-IMPLANTACION-20260430","title":"Plano del fabricante: implantación de equipos · referencia E7","sheet":"Espacio modelo; referencia E7 en el nombre del archivo","date":"2026-04-30"},"cadSource":"equipment_layout.dxf","conversion":"ODA","sourceInsertHandle":"8355F","limitations":["Cuerpo horizontal reconstruido por revolución del perfil axial del fabricante, con los extremos segmentados originales y cuatro bridas axiales.","La altura de los soportes y la cota del eje no están documentadas. Se adopta exclusivamente para visualización un eje a 0,50 m sobre el plano de apoyo; las bridas quedan a 0,275 m de este plano.","No se modelan soportes ni conexiones cuya altura no está documentada; los círculos de conexiones en planta no determinan su longitud vertical.","El modelo es una envolvente maciza de referencia; no representa espesores de pared, chapas, pernos ni componentes internos."],"shape":"Revolución de perfil axial con fondos segmentados y cuatro bridas","unmodeledFeatures":["Soportes: altura no documentada","Boquillas: longitud y elevación no documentadas","Pernos, espesores e interiores: no documentados"]} | {"boundingBoxM":{"min":[46.536949,46.951083,1.575],"max":[47.330076,49.929069,2.025]},"extentsM":[0.793126,2.977987,0.45],"meshSurfaceM2":4.439517,"meshVolumeM3":0.25246,"closedSolid":true,"basis":"Magnitudes de las mallas representadas, no cantidades certificadas de obra, compra o fabricación. Las partes pueden compartir superficies; no se suman como un despiece de materiales."} | {"elementId":"WE441-PLAN","ifcGuid":"2dCPUcLsjLzAxiSzTM1uze","ifcClass":"IfcHeatExchanger","buildingId":"process_plant","buildingName":"Planta de proceso","sourceDocumentId":"EQ-IMPLANTACION-20260430","sourceRepresentationKind":"equipment"} | 8355F
Posenfriador horizontal WE442 · cuerpo, fondos y bridas | WE442-PLAN | ["found_0904_91ddea20df6ae4","found_0904_3cc1af80838d89","found_0904_3470dba61bdc9f","found_0904_36db625c917a9f","found_0904_7f59eb478aceab","found_0904_bc31102c2a4499"] | {"source":{"documentId":"EQ-IMPLANTACION-20260430","title":"Plano del fabricante: implantación de equipos · referencia E7","sheet":"Espacio modelo; referencia E7 en el nombre del archivo","date":"2026-04-30"},"cadSource":"equipment_layout.dxf","conversion":"ODA","sourceInsertHandle":"8356A","limitations":["Cuerpo horizontal reconstruido por revolución del perfil axial del fabricante, con los extremos segmentados originales y cuatro bridas axiales.","La altura de los soportes y la cota del eje no están documentadas. Se adopta exclusivamente para visualización un eje a 0,50 m sobre el plano de apoyo; las bridas quedan a 0,275 m de este plano.","No se modelan soportes ni conexiones cuya altura no está documentada; los círculos de conexiones en planta no determinan su longitud vertical.","El modelo es una envolvente maciza de referencia; no representa espesores de pared, chapas, pernos ni componentes internos."],"shape":"Revolución de perfil axial con fondos segmentados y cuatro bridas","unmodeledFeatures":["Soportes: altura no documentada","Boquillas: longitud y elevación no documentadas","Pernos, espesores e interiores: no documentados"]} | {"boundingBoxM":{"min":[47.923903,46.760397,1.575],"max":[48.717029,49.738384,2.025]},"extentsM":[0.793126,2.977987,0.45],"meshSurfaceM2":4.439517,"meshVolumeM3":0.25246,"closedSolid":true,"basis":"Magnitudes de las mallas representadas, no cantidades certificadas de obra, compra o fabricación. Las partes pueden compartir superficies; no se suman como un despiece de materiales."} | {"elementId":"WE442-PLAN","ifcGuid":"0A3g_wNrHRpxd2vEMoS7CQ","ifcClass":"IfcHeatExchanger","buildingId":"process_plant","buildingName":"Planta de proceso","sourceDocumentId":"EQ-IMPLANTACION-20260430","sourceRepresentationKind":"equipment"} | 8356A

# IfcLightFixture: Luminaria del entorno · ilustrativa 1
In: Parcela industrial Jinhong
Description: Entorno de coordinación: trazados derivados de las fuentes indicadas por elemento; cotas, espesores, acabados y mobiliario orientativos cuando no están documentados. No acredita propiedad, servidumbres ni cantidades de obra y no es una base de construcción.; PredefinedType: USERDEFINED; Document: Indicación del cliente · entorno de 200 m con aparcamientos y luminarias ilustrativos; Entorno de Expacio Mérida · Catastro INSPIRE, PNOA y levantamiento Berrio; Levantamiento Berrio · parcelas I-27 Vial 3 e I-18 Vial 4; IGN · ortofotografía PNOA de máxima actualidad; Group: BIM · Entorno · aparcamientos y luminarias
JH_InformacionBIM - buildingId: context; buildingName: Entorno exterior de la parcela; level: Exterior · contexto de 200 m; category: Luminaria del entorno · ilustrativa 1; ifcClass: IfcLightFixture; status: provisional; source: {"documentId":"JH-CLIENT-CONTEXT-20260909","title":"Indicación del cliente · entorno de 200 m con aparcamientos y luminarias ilustrativos","date":"2026-09-09","note":"Distribución aproximada autorizada. No acredita la posición ni el número real de plazas o farolas existentes."}; material: {"name":"Luminaria exterior · gris","status":"provisional","source":"Acabado visual aproximado; no especificación de proyecto."}; appearance: {"profileId":"ctx_light","name":"Luminaria exterior · gris","status":"criterio_visual","basis":"Acabado de contexto orientativo, sin especificación de obra."}; dimensions: {"documented":[],"assumed":[{"label":"Altura de poste","value":8,"unit":"m"},{"label":"Vuelo de brazo","value":1.4,"unit":"m"}],"geometry":[]}; classification: {"layerId":"context_furniture","layerName":"Entorno · aparcamientos y luminarias","function":"Luminaria del entorno · ilustrativa 1"}; visualLayer: {"id":"context_furniture","name":"Entorno · aparcamientos y luminarias","defaultVisible":false}; representationKind: entorno_ilustrativo; quantityEligible: no; positioning: {"Sistema":"ETRS89 / UTM 29N · metros","Origen del modelo":"X 729400 · Y 4301550 · Z 285 m","Alcance":"Hasta 200 m desde el lindero del proyecto; solo exterior de parcela","Planta":"Distribución ilustrativa autorizada","Altimetría":"Plano ajustado a 213 puntos XYZ de aceras, extrapolado al resto del contexto; no es un MDT levantado"}; issues: ["Contexto para lectura del emplazamiento; planta derivada de cartografía, cotas y detalles simplificados. No para construcción ni mediciones de obra.","Las mediciones en el entorno expresan la geometría representada y conservan la precisión de su fuente."]; conceptual: {"enabled":true,"basis":"Distribución aproximada autorizada. No acredita la posición ni el número real de plazas o farolas existentes.","pending":["Posición real del mobiliario","Dimensiones y niveles definitivos"]}; geometryMetrics: {"boundingBoxM":{"min":[-20.964535,-79.282823,0.118432],"max":[-19.054452,-78.800589,8.228432]},"extentsM":[1.910083,0.482234,8.11],"meshSurfaceM2":5.532365,"meshVolumeM3":0.181319,"closedSolid":true,"basis":"Entorno de coordinación: trazados derivados de las fuentes indicadas por elemento; cotas, espesores, acabados y mobiliario orientativos cuando no están documentados. No acredita propiedad, servidumbres ni cantidades de obra y no es una base de construcción."}
JH_Trazabilidad - Origen: Indicación del cliente · entorno de 200 m con aparcamientos y luminarias ilustrativos; Estado: provisional; Capa BIM: Entorno · aparcamientos y luminarias; Mediciones de obra: Excluido; Identificador: CTX-LIGHT-01; Categoria: Luminaria del entorno · ilustrativa 1; ClaseIFC: IfcLightFixture; EstadoDeInformacion: provisional; DocumentoFuente: {"documentId":"JH-CLIENT-CONTEXT-20260909","title":"Indicación del cliente · entorno de 200 m con aparcamientos y luminarias ilustrativos","date":"2026-09-09","note":"Distribución aproximada autorizada. No acredita la posición ni el número real de plazas o farolas existentes."}; IncidenciasPendientes: ["Contexto para lectura del emplazamiento; planta derivada de cartografía, cotas y detalles simplificados. No para construcción ni mediciones de obra.","Las mediciones en el entorno expresan la geometría representada y conservan la precisión de su fuente."]; UsoDeLasMagnitudes: Entorno de coordinación: trazados derivados de las fuentes indicadas por elemento; cotas, espesores, acabados y mobiliario orientativos cuando no están documentados. No acredita propiedad, servidumbres ni cantidades de obra y no es una base de construcción.
JH_CriterioDePosicion - PosicionYEstado: {"Sistema":"ETRS89 / UTM 29N · metros","Origen del modelo":"X 729400 · Y 4301550 · Z 285 m","Alcance":"Hasta 200 m desde el lindero del proyecto; solo exterior de parcela","Planta":"Distribución ilustrativa autorizada","Altimetría":"Plano ajustado a 213 puntos XYZ de aceras, extrapolado al resto del contexto; no es un MDT levantado"}
JH_EvidenciaDeMaterial - name: Luminaria exterior · gris; status: provisional; source: Acabado visual aproximado; no especificación de proyecto.
JH_CapaBIM - IdentificadorCapa: context_furniture; NombreCapa: Entorno · aparcamientos y luminarias; Funcion: Luminaria del entorno · ilustrativa 1; VisibilidadInicial: no
JH_EntornoContexto - Estado: provisional; Origen: {"documentId":"JH-CLIENT-CONTEXT-20260909","title":"Indicación del cliente · entorno de 200 m con aparcamientos y luminarias ilustrativos","date":"2026-09-09","note":"Distribución aproximada autorizada. No acredita la posición ni el número real de plazas o farolas existentes."}; Posicion: {"Sistema":"ETRS89 / UTM 29N · metros","Origen del modelo":"X 729400 · Y 4301550 · Z 285 m","Alcance":"Hasta 200 m desde el lindero del proyecto; solo exterior de parcela","Planta":"Distribución ilustrativa autorizada","Altimetría":"Plano ajustado a 213 puntos XYZ de aceras, extrapolado al resto del contexto; no es un MDT levantado"}; DimensionesSupuestas: [{"label":"Altura de poste","value":8,"unit":"m"},{"label":"Vuelo de brazo","value":1.4,"unit":"m"}]; IncluirEnMediciones: no; EsquemaIlustrativo: yes; Criterio: Entorno de coordinación: trazados derivados de las fuentes indicadas por elemento; cotas, espesores, acabados y mobiliario orientativos cuando no están documentados. No acredita propiedad, servidumbres ni cantidades de obra y no es una base de construcción.
JH_EsquemaProvisional - Estado: No para construcción; Origen: {"documentId":"JH-CLIENT-CONTEXT-20260909","title":"Indicación del cliente · entorno de 200 m con aparcamientos y luminarias ilustrativos","date":"2026-09-09","note":"Distribución aproximada autorizada. No acredita la posición ni el número real de plazas o farolas existentes."}; DimensionesSupuestas: [{"label":"Altura de poste","value":8,"unit":"m"},{"label":"Vuelo de brazo","value":1.4,"unit":"m"}]; Posicion: {"Sistema":"ETRS89 / UTM 29N · metros","Origen del modelo":"X 729400 · Y 4301550 · Z 285 m","Alcance":"Hasta 200 m desde el lindero del proyecto; solo exterior de parcela","Planta":"Distribución ilustrativa autorizada","Altimetría":"Plano ajustado a 213 puntos XYZ de aceras, extrapolado al resto del contexto; no es un MDT levantado"}; IncluirEnMediciones: no; Criterio: {"enabled":true,"basis":"Distribución aproximada autorizada. No acredita la posición ni el número real de plazas o farolas existentes.","pending":["Posición real del mobiliario","Dimensiones y niveles definitivos"]}

# IfcLightFixture: Luminaria del entorno · ilustrativa 10
In: Parcela industrial Jinhong
Description: Entorno de coordinación: trazados derivados de las fuentes indicadas por elemento; cotas, espesores, acabados y mobiliario orientativos cuando no están documentados. No acredita propiedad, servidumbres ni cantidades de obra y no es una base de construcción.; PredefinedType: USERDEFINED; Document: Indicación del cliente · entorno de 200 m con aparcamientos y luminarias ilustrativos; Entorno de Expacio Mérida · Catastro INSPIRE, PNOA y levantamiento Berrio; Levantamiento Berrio · parcelas I-27 Vial 3 e I-18 Vial 4; IGN · ortofotografía PNOA de máxima actualidad; Group: BIM · Entorno · aparcamientos y luminarias
JH_InformacionBIM - buildingId: context; buildingName: Entorno exterior de la parcela; level: Exterior · contexto de 200 m; category: Luminaria del entorno · ilustrativa 10; ifcClass: IfcLightFixture; status: provisional; source: {"documentId":"JH-CLIENT-CONTEXT-20260909","title":"Indicación del cliente · entorno de 200 m con aparcamientos y luminarias ilustrativos","date":"2026-09-09","note":"Distribución aproximada autorizada. No acredita la posición ni el número real de plazas o farolas existentes."}; material: {"name":"Luminaria exterior · gris","status":"provisional","source":"Acabado visual aproximado; no especificación de proyecto."}; appearance: {"profileId":"ctx_light","name":"Luminaria exterior · gris","status":"criterio_visual","basis":"Acabado de contexto orientativo, sin especificación de obra."}; dimensions: {"documented":[],"assumed":[{"label":"Altura de poste","value":8,"unit":"m"},{"label":"Vuelo de brazo","value":1.4,"unit":"m"}],"geometry":[]}; classification: {"layerId":"context_furniture","layerName":"Entorno · aparcamientos y luminarias","function":"Luminaria del entorno · ilustrativa 10"}; visualLayer: {"id":"context_furniture","name":"Entorno · aparcamientos y luminarias","defaultVisible":false}; representationKind: entorno_ilustrativo; quantityEligible: no; positioning: {"Sistema":"ETRS89 / UTM 29N · metros","Origen del modelo":"X 729400 · Y 4301550 · Z 285 m","Alcance":"Hasta 200 m desde el lindero del proyecto; solo exterior de parcela","Planta":"Distribución ilustrativa autorizada","Altimetría":"Plano ajustado a 213 puntos XYZ de aceras, extrapolado al resto del contexto; no es un MDT levantado"}; issues: ["Contexto para lectura del emplazamiento; planta derivada de cartografía, cotas y detalles simplificados. No para construcción ni mediciones de obra.","Las mediciones en el entorno expresan la geometría representada y conservan la precisión de su fuente."]; conceptual: {"enabled":true,"basis":"Distribución aproximada autorizada. No acredita la posición ni el número real de plazas o farolas existentes.","pending":["Posición real del mobiliario","Dimensiones y niveles definitivos"]}; geometryMetrics: {"boundingBoxM":{"min":[-190.054317,43.186709,-1.487877],"max":[-189.348282,44.938614,6.622123]},"extentsM":[0.706035,1.751905,8.11],"meshSurfaceM2":5.532365,"meshVolumeM3":0.181319,"closedSolid":true,"basis":"Entorno de coordinación: trazados derivados de las fuentes indicadas por elemento; cotas, espesores, acabados y mobiliario orientativos cuando no están documentados. No acredita propiedad, servidumbres ni cantidades de obra y no es una base de construcción."}
JH_Trazabilidad - Origen: Indicación del cliente · entorno de 200 m con aparcamientos y luminarias ilustrativos; Estado: provisional; Capa BIM: Entorno · aparcamientos y luminarias; Mediciones de obra: Excluido; Identificador: CTX-LIGHT-10; Categoria: Luminaria del entorno · ilustrativa 10; ClaseIFC: IfcLightFixture; EstadoDeInformacion: provisional; DocumentoFuente: {"documentId":"JH-CLIENT-CONTEXT-20260909","title":"Indicación del cliente · entorno de 200 m con aparcamientos y luminarias ilustrativos","date":"2026-09-09","note":"Distribución aproximada autorizada. No acredita la posición ni el número real de plazas o farolas existentes."}; IncidenciasPendientes: ["Contexto para lectura del emplazamiento; planta derivada de cartografía, cotas y detalles simplificados. No para construcción ni mediciones de obra.","Las mediciones en el entorno expresan la geometría representada y conservan la precisión de su fuente."]; UsoDeLasMagnitudes: Entorno de coordinación: trazados derivados de las fuentes indicadas por elemento; cotas, espesores, acabados y mobiliario orientativos cuando no están documentados. No acredita propiedad, servidumbres ni cantidades de obra y no es una base de construcción.
JH_CriterioDePosicion - PosicionYEstado: {"Sistema":"ETRS89 / UTM 29N · metros","Origen del modelo":"X 729400 · Y 4301550 · Z 285 m","Alcance":"Hasta 200 m desde el lindero del proyecto; solo exterior de parcela","Planta":"Distribución ilustrativa autorizada","Altimetría":"Plano ajustado a 213 puntos XYZ de aceras, extrapolado al resto del contexto; no es un MDT levantado"}
JH_EvidenciaDeMaterial - name: Luminaria exterior · gris; status: provisional; source: Acabado visual aproximado; no especificación de proyecto.
JH_CapaBIM - IdentificadorCapa: context_furniture; NombreCapa: Entorno · aparcamientos y luminarias; Funcion: Luminaria del entorno · ilustrativa 10; VisibilidadInicial: no
JH_EntornoContexto - Estado: provisional; Origen: {"documentId":"JH-CLIENT-CONTEXT-20260909","title":"Indicación del cliente · entorno de 200 m con aparcamientos y luminarias ilustrativos","date":"2026-09-09","note":"Distribución aproximada autorizada. No acredita la posición ni el número real de plazas o farolas existentes."}; Posicion: {"Sistema":"ETRS89 / UTM 29N · metros","Origen del modelo":"X 729400 · Y 4301550 · Z 285 m","Alcance":"Hasta 200 m desde el lindero del proyecto; solo exterior de parcela","Planta":"Distribución ilustrativa autorizada","Altimetría":"Plano ajustado a 213 puntos XYZ de aceras, extrapolado al resto del contexto; no es un MDT levantado"}; DimensionesSupuestas: [{"label":"Altura de poste","value":8,"unit":"m"},{"label":"Vuelo de brazo","value":1.4,"unit":"m"}]; IncluirEnMediciones: no; EsquemaIlustrativo: yes; Criterio: Entorno de coordinación: trazados derivados de las fuentes indicadas por elemento; cotas, espesores, acabados y mobiliario orientativos cuando no están documentados. No acredita propiedad, servidumbres ni cantidades de obra y no es una base de construcción.
JH_EsquemaProvisional - Estado: No para construcción; Origen: {"documentId":"JH-CLIENT-CONTEXT-20260909","title":"Indicación del cliente · entorno de 200 m con aparcamientos y luminarias ilustrativos","date":"2026-09-09","note":"Distribución aproximada autorizada. No acredita la posición ni el número real de plazas o farolas existentes."}; DimensionesSupuestas: [{"label":"Altura de poste","value":8,"unit":"m"},{"label":"Vuelo de brazo","value":1.4,"unit":"m"}]; Posicion: {"Sistema":"ETRS89 / UTM 29N · metros","Origen del modelo":"X 729400 · Y 4301550 · Z 285 m","Alcance":"Hasta 200 m desde el lindero del proyecto; solo exterior de parcela","Planta":"Distribución ilustrativa autorizada","Altimetría":"Plano ajustado a 213 puntos XYZ de aceras, extrapolado al resto del contexto; no es un MDT levantado"}; IncluirEnMediciones: no; Criterio: {"enabled":true,"basis":"Distribución aproximada autorizada. No acredita la posición ni el número real de plazas o farolas existentes.","pending":["Posición real del mobiliario","Dimensiones y niveles definitivos"]}

# IfcLightFixture: Luminaria del entorno · ilustrativa 11
In: Parcela industrial Jinhong
Description: Entorno de coordinación: trazados derivados de las fuentes indicadas por elemento; cotas, espesores, acabados y mobiliario orientativos cuando no están documentados. No acredita propiedad, servidumbres ni cantidades de obra y no es una base de construcción.; PredefinedType: USERDEFINED; Document: Indicación del cliente · entorno de 200 m con aparcamientos y luminarias ilustrativos; Entorno de Expacio Mérida · Catastro INSPIRE, PNOA y levantamiento Berrio; Levantamiento Berrio · parcelas I-27 Vial 3 e I-18 Vial 4; IGN · ortofotografía PNOA de máxima actualidad; Group: BIM · Entorno · aparcamientos y luminarias
JH_InformacionBIM - buildingId: context; buildingName: Entorno exterior de la parcela; level: Exterior · contexto de 200 m; category: Luminaria del entorno · ilustrativa 11; ifcClass: IfcLightFixture; status: provisional; source: {"documentId":"JH-CLIENT-CONTEXT-20260909","title":"Indicación del cliente · entorno de 200 m con aparcamientos y luminarias ilustrativos","date":"2026-09-09","note":"Distribución aproximada autorizada. No acredita la posición ni el número real de plazas o farolas existentes."}; material: {"name":"Luminaria exterior · gris","status":"provisional","source":"Acabado visual aproximado; no especificación de proyecto."}; appearance: {"profileId":"ctx_light","name":"Luminaria exterior · gris","status":"criterio_visual","basis":"Acabado de contexto orientativo, sin especificación de obra."}; dimensions: {"documented":[],"assumed":[{"label":"Altura de poste","value":8,"unit":"m"},{"label":"Vuelo de brazo","value":1.4,"unit":"m"}],"geometry":[]}; classification: {"layerId":"context_furniture","layerName":"Entorno · aparcamientos y luminarias","function":"Luminaria del entorno · ilustrativa 11"}; visualLayer: {"id":"context_furniture","name":"Entorno · aparcamientos y luminarias","defaultVisible":false}; representationKind: entorno_ilustrativo; quantityEligible: no; positioning: {"Sistema":"ETRS89 / UTM 29N · metros","Origen del modelo":"X 729400 · Y 4301550 · Z 285 m","Alcance":"Hasta 200 m desde el lindero del proyecto; solo exterior de parcela","Planta":"Distribución ilustrativa autorizada","Altimetría":"Plano ajustado a 213 puntos XYZ de aceras, extrapolado al resto del contexto; no es un MDT levantado"}; issues: ["Contexto para lectura del emplazamiento; planta derivada de cartografía, cotas y detalles simplificados. No para construcción ni mediciones de obra.","Las mediciones en el entorno expresan la geometría representada y conservan la precisión de su fuente."]; conceptual: {"enabled":true,"basis":"Distribución aproximada autorizada. No acredita la posición ni el número real de plazas o farolas existentes.","pending":["Posición real del mobiliario","Dimensiones y niveles definitivos"]}; geometryMetrics: {"boundingBoxM":{"min":[-158.35363,38.820195,-1.139031],"max":[-157.647595,40.5721,6.970969]},"extentsM":[0.706035,1.751905,8.11],"meshSurfaceM2":5.532365,"meshVolumeM3":0.181319,"closedSolid":true,"basis":"Entorno de coordinación: trazados derivados de las fuentes indicadas por elemento; cotas, espesores, acabados y mobiliario orientativos cuando no están documentados. No acredita propiedad, servidumbres ni cantidades de obra y no es una base de construcción."}
JH_Trazabilidad - Origen: Indicación del cliente · entorno de 200 m con aparcamientos y luminarias ilustrativos; Estado: provisional; Capa BIM: Entorno · aparcamientos y luminarias; Mediciones de obra: Excluido; Identificador: CTX-LIGHT-11; Categoria: Luminaria del entorno · ilustrativa 11; ClaseIFC: IfcLightFixture; EstadoDeInformacion: provisional; DocumentoFuente: {"documentId":"JH-CLIENT-CONTEXT-20260909","title":"Indicación del cliente · entorno de 200 m con aparcamientos y luminarias ilustrativos","date":"2026-09-09","note":"Distribución aproximada autorizada. No acredita la posición ni el número real de plazas o farolas existentes."}; IncidenciasPendientes: ["Contexto para lectura del emplazamiento; planta derivada de cartografía, cotas y detalles simplificados. No para construcción ni mediciones de obra.","Las mediciones en el entorno expresan la geometría representada y conservan la precisión de su fuente."]; UsoDeLasMagnitudes: Entorno de coordinación: trazados derivados de las fuentes indicadas por elemento; cotas, espesores, acabados y mobiliario orientativos cuando no están documentados. No acredita propiedad, servidumbres ni cantidades de obra y no es una base de construcción.
JH_CriterioDePosicion - PosicionYEstado: {"Sistema":"ETRS89 / UTM 29N · metros","Origen del modelo":"X 729400 · Y 4301550 · Z 285 m","Alcance":"Hasta 200 m desde el lindero del proyecto; solo exterior de parcela","Planta":"Distribución ilustrativa autorizada","Altimetría":"Plano ajustado a 213 puntos XYZ de aceras, extrapolado al resto del contexto; no es un MDT levantado"}
JH_EvidenciaDeMaterial - name: Luminaria exterior · gris; status: provisional; source: Acabado visual aproximado; no especificación de proyecto.
JH_CapaBIM - IdentificadorCapa: context_furniture; NombreCapa: Entorno · aparcamientos y luminarias; Funcion: Luminaria del entorno · ilustrativa 11; VisibilidadInicial: no
JH_EntornoContexto - Estado: provisional; Origen: {"documentId":"JH-CLIENT-CONTEXT-20260909","title":"Indicación del cliente · entorno de 200 m con aparcamientos y luminarias ilustrativos","date":"2026-09-09","note":"Distribución aproximada autorizada. No acredita la posición ni el número real de plazas o farolas existentes."}; Posicion: {"Sistema":"ETRS89 / UTM 29N · metros","Origen del modelo":"X 729400 · Y 4301550 · Z 285 m","Alcance":"Hasta 200 m desde el lindero del proyecto; solo exterior de parcela","Planta":"Distribución ilustrativa autorizada","Altimetría":"Plano ajustado a 213 puntos XYZ de aceras, extrapolado al resto del contexto; no es un MDT levantado"}; DimensionesSupuestas: [{"label":"Altura de poste","value":8,"unit":"m"},{"label":"Vuelo de brazo","value":1.4,"unit":"m"}]; IncluirEnMediciones: no; EsquemaIlustrativo: yes; Criterio: Entorno de coordinación: trazados derivados de las fuentes indicadas por elemento; cotas, espesores, acabados y mobiliario orientativos cuando no están documentados. No acredita propiedad, servidumbres ni cantidades de obra y no es una base de construcción.
JH_EsquemaProvisional - Estado: No para construcción; Origen: {"documentId":"JH-CLIENT-CONTEXT-20260909","title":"Indicación del cliente · entorno de 200 m con aparcamientos y luminarias ilustrativos","date":"2026-09-09","note":"Distribución aproximada autorizada. No acredita la posición ni el número real de plazas o farolas existentes."}; DimensionesSupuestas: [{"label":"Altura de poste","value":8,"unit":"m"},{"label":"Vuelo de brazo","value":1.4,"unit":"m"}]; Posicion: {"Sistema":"ETRS89 / UTM 29N · metros","Origen del modelo":"X 729400 · Y 4301550 · Z 285 m","Alcance":"Hasta 200 m desde el lindero del proyecto; solo exterior de parcela","Planta":"Distribución ilustrativa autorizada","Altimetría":"Plano ajustado a 213 puntos XYZ de aceras, extrapolado al resto del contexto; no es un MDT levantado"}; IncluirEnMediciones: no; Criterio: {"enabled":true,"basis":"Distribución aproximada autorizada. No acredita la posición ni el número real de plazas o farolas existentes.","pending":["Posición real del mobiliario","Dimensiones y niveles definitivos"]}

# IfcLightFixture: Luminaria del entorno · ilustrativa 12
In: Parcela industrial Jinhong
Description: Entorno de coordinación: trazados derivados de las fuentes indicadas por elemento; cotas, espesores, acabados y mobiliario orientativos cuando no están documentados. No acredita propiedad, servidumbres ni cantidades de obra y no es una base de construcción.; PredefinedType: USERDEFINED; Document: Indicación del cliente · entorno de 200 m con aparcamientos y luminarias ilustrativos; Entorno de Expacio Mérida · Catastro INSPIRE, PNOA y levantamiento Berrio; Levantamiento Berrio · parcelas I-27 Vial 3 e I-18 Vial 4; IGN · ortofotografía PNOA de máxima actualidad; Group: BIM · Entorno · aparcamientos y luminarias
JH_InformacionBIM - buildingId: context; buildingName: Entorno exterior de la parcela; level: Exterior · contexto de 200 m; category: Luminaria del entorno · ilustrativa 12; ifcClass: IfcLightFixture; status: provisional; source: {"documentId":"JH-CLIENT-CONTEXT-20260909","title":"Indicación del cliente · entorno de 200 m con aparcamientos y luminarias ilustrativos","date":"2026-09-09","note":"Distribución aproximada autorizada. No acredita la posición ni el número real de plazas o farolas existentes."}; material: {"name":"Luminaria exterior · gris","status":"provisional","source":"Acabado visual aproximado; no especificación de proyecto."}; appearance: {"profileId":"ctx_light","name":"Luminaria exterior · gris","status":"criterio_visual","basis":"Acabado de contexto orientativo, sin especificación de obra."}; dimensions: {"documented":[],"assumed":[{"label":"Altura de poste","value":8,"unit":"m"},{"label":"Vuelo de brazo","value":1.4,"unit":"m"}],"geometry":[]}; classification: {"layerId":"context_furniture","layerName":"Entorno · aparcamientos y luminarias","function":"Luminaria del entorno · ilustrativa 12"}; visualLayer: {"id":"context_furniture","name":"Entorno · aparcamientos y luminarias","defaultVisible":false}; representationKind: entorno_ilustrativo; quantityEligible: no; positioning: {"Sistema":"ETRS89 / UTM 29N · metros","Origen del modelo":"X 729400 · Y 4301550 · Z 285 m","Alcance":"Hasta 200 m desde el lindero del proyecto; solo exterior de parcela","Planta":"Distribución ilustrativa autorizada","Altimetría":"Plano ajustado a 213 puntos XYZ de aceras, extrapolado al resto del contexto; no es un MDT levantado"}; issues: ["Contexto para lectura del emplazamiento; planta derivada de cartografía, cotas y detalles simplificados. No para construcción ni mediciones de obra.","Las mediciones en el entorno expresan la geometría representada y conservan la precisión de su fuente."]; conceptual: {"enabled":true,"basis":"Distribución aproximada autorizada. No acredita la posición ni el número real de plazas o farolas existentes.","pending":["Posición real del mobiliario","Dimensiones y niveles definitivos"]}; geometryMetrics: {"boundingBoxM":{"min":[-126.584716,34.949004,-0.788088],"max":[-125.878681,36.700909,7.321912]},"extentsM":[0.706035,1.751905,8.11],"meshSurfaceM2":5.532364,"meshVolumeM3":0.181319,"closedSolid":true,"basis":"Entorno de coordinación: trazados derivados de las fuentes indicadas por elemento; cotas, espesores, acabados y mobiliario orientativos cuando no están documentados. No acredita propiedad, servidumbres ni cantidades de obra y no es una base de construcción."}
JH_Trazabilidad - Origen: Indicación del cliente · entorno de 200 m con aparcamientos y luminarias ilustrativos; Estado: provisional; Capa BIM: Entorno · aparcamientos y luminarias; Mediciones de obra: Excluido; Identificador: CTX-LIGHT-12; Categoria: Luminaria del entorno · ilustrativa 12; ClaseIFC: IfcLightFixture; EstadoDeInformacion: provisional; DocumentoFuente: {"documentId":"JH-CLIENT-CONTEXT-20260909","title":"Indicación del cliente · entorno de 200 m con aparcamientos y luminarias ilustrativos","date":"2026-09-09","note":"Distribución aproximada autorizada. No acredita la posición ni el número real de plazas o farolas existentes."}; IncidenciasPendientes: ["Contexto para lectura del emplazamiento; planta derivada de cartografía, cotas y detalles simplificados. No para construcción ni mediciones de obra.","Las mediciones en el entorno expresan la geometría representada y conservan la precisión de su fuente."]; UsoDeLasMagnitudes: Entorno de coordinación: trazados derivados de las fuentes indicadas por elemento; cotas, espesores, acabados y mobiliario orientativos cuando no están documentados. No acredita propiedad, servidumbres ni cantidades de obra y no es una base de construcción.
JH_CriterioDePosicion - PosicionYEstado: {"Sistema":"ETRS89 / UTM 29N · metros","Origen del modelo":"X 729400 · Y 4301550 · Z 285 m","Alcance":"Hasta 200 m desde el lindero del proyecto; solo exterior de parcela","Planta":"Distribución ilustrativa autorizada","Altimetría":"Plano ajustado a 213 puntos XYZ de aceras, extrapolado al resto del contexto; no es un MDT levantado"}
JH_EvidenciaDeMaterial - name: Luminaria exterior · gris; status: provisional; source: Acabado visual aproximado; no especificación de proyecto.
JH_CapaBIM - IdentificadorCapa: context_furniture; NombreCapa: Entorno · aparcamientos y luminarias; Funcion: Luminaria del entorno · ilustrativa 12; VisibilidadInicial: no
JH_EntornoContexto - Estado: provisional; Origen: {"documentId":"JH-CLIENT-CONTEXT-20260909","title":"Indicación del cliente · entorno de 200 m con aparcamientos y luminarias ilustrativos","date":"2026-09-09","note":"Distribución aproximada autorizada. No acredita la posición ni el número real de plazas o farolas existentes."}; Posicion: {"Sistema":"ETRS89 / UTM 29N · metros","Origen del modelo":"X 729400 · Y 4301550 · Z 285 m","Alcance":"Hasta 200 m desde el lindero del proyecto; solo exterior de parcela","Planta":"Distribución ilustrativa autorizada","Altimetría":"Plano ajustado a 213 puntos XYZ de aceras, extrapolado al resto del contexto; no es un MDT levantado"}; DimensionesSupuestas: [{"label":"Altura de poste","value":8,"unit":"m"},{"label":"Vuelo de brazo","value":1.4,"unit":"m"}]; IncluirEnMediciones: no; EsquemaIlustrativo: yes; Criterio: Entorno de coordinación: trazados derivados de las fuentes indicadas por elemento; cotas, espesores, acabados y mobiliario orientativos cuando no están documentados. No acredita propiedad, servidumbres ni cantidades de obra y no es una base de construcción.
JH_EsquemaProvisional - Estado: No para construcción; Origen: {"documentId":"JH-CLIENT-CONTEXT-20260909","title":"Indicación del cliente · entorno de 200 m con aparcamientos y luminarias ilustrativos","date":"2026-09-09","note":"Distribución aproximada autorizada. No acredita la posición ni el número real de plazas o farolas existentes."}; DimensionesSupuestas: [{"label":"Altura de poste","value":8,"unit":"m"},{"label":"Vuelo de brazo","value":1.4,"unit":"m"}]; Posicion: {"Sistema":"ETRS89 / UTM 29N · metros","Origen del modelo":"X 729400 · Y 4301550 · Z 285 m","Alcance":"Hasta 200 m desde el lindero del proyecto; solo exterior de parcela","Planta":"Distribución ilustrativa autorizada","Altimetría":"Plano ajustado a 213 puntos XYZ de aceras, extrapolado al resto del contexto; no es un MDT levantado"}; IncluirEnMediciones: no; Criterio: {"enabled":true,"basis":"Distribución aproximada autorizada. No acredita la posición ni el número real de plazas o farolas existentes.","pending":["Posición real del mobiliario","Dimensiones y niveles definitivos"]}

# IfcLightFixture: Luminaria del entorno · ilustrativa 13
In: Parcela industrial Jinhong
Description: Entorno de coordinación: trazados derivados de las fuentes indicadas por elemento; cotas, espesores, acabados y mobiliario orientativos cuando no están documentados. No acredita propiedad, servidumbres ni cantidades de obra y no es una base de construcción.; PredefinedType: USERDEFINED; Document: Indicación del cliente · entorno de 200 m con aparcamientos y luminarias ilustrativos; Entorno de Expacio Mérida · Catastro INSPIRE, PNOA y levantamiento Berrio; Levantamiento Berrio · parcelas I-27 Vial 3 e I-18 Vial 4; IGN · ortofotografía PNOA de máxima actualidad; Group: BIM · Entorno · aparcamientos y luminarias
JH_InformacionBIM - buildingId: context; buildingName: Entorno exterior de la parcela; level: Exterior · contexto de 200 m; category: Luminaria del entorno · ilustrativa 13; ifcClass: IfcLightFixture; status: provisional; source: {"documentId":"JH-CLIENT-CONTEXT-20260909","title":"Indicación del cliente · entorno de 200 m con aparcamientos y luminarias ilustrativos","date":"2026-09-09","note":"Distribución aproximada autorizada. No acredita la posición ni el número real de plazas o farolas existentes."}; material: {"name":"Luminaria exterior · gris","status":"provisional","source":"Acabado visual aproximado; no especificación de proyecto."}; appearance: {"profileId":"ctx_light","name":"Luminaria exterior · gris","status":"criterio_visual","basis":"Acabado de contexto orientativo, sin especificación de obra."}; dimensions: {"documented":[],"assumed":[{"label":"Altura de poste","value":8,"unit":"m"},{"label":"Vuelo de brazo","value":1.4,"unit":"m"}],"geometry":[]}; classification: {"layerId":"context_furniture","layerName":"Entorno · aparcamientos y luminarias","function":"Luminaria del entorno · ilustrativa 13"}; visualLayer: {"id":"context_furniture","name":"Entorno · aparcamientos y luminarias","defaultVisible":false}; representationKind: entorno_ilustrativo; quantityEligible: no; positioning: {"Sistema":"ETRS89 / UTM 29N · metros","Origen del modelo":"X 729400 · Y 4301550 · Z 285 m","Alcance":"Hasta 200 m desde el lindero del proyecto; solo exterior de parcela","Planta":"Distribución ilustrativa autorizada","Altimetría":"Plano ajustado a 213 puntos XYZ de aceras, extrapolado al resto del contexto; no es un MDT levantado"}; issues: ["Contexto para lectura del emplazamiento; planta derivada de cartografía, cotas y detalles simplificados. No para construcción ni mediciones de obra.","Las mediciones en el entorno expresan la geometría representada y conservan la precisión de su fuente."]; conceptual: {"enabled":true,"basis":"Distribución aproximada autorizada. No acredita la posición ni el número real de plazas o farolas existentes.","pending":["Posición real del mobiliario","Dimensiones y niveles definitivos"]}; geometryMetrics: {"boundingBoxM":{"min":[-94.884029,30.58249,-0.439242],"max":[-94.177994,32.334395,7.670758]},"extentsM":[0.706035,1.751905,8.11],"meshSurfaceM2":5.532367,"meshVolumeM3":0.181319,"closedSolid":true,"basis":"Entorno de coordinación: trazados derivados de las fuentes indicadas por elemento; cotas, espesores, acabados y mobiliario orientativos cuando no están documentados. No acredita propiedad, servidumbres ni cantidades de obra y no es una base de construcción."}
JH_Trazabilidad - Origen: Indicación del cliente · entorno de 200 m con aparcamientos y luminarias ilustrativos; Estado: provisional; Capa BIM: Entorno · aparcamientos y luminarias; Mediciones de obra: Excluido; Identificador: CTX-LIGHT-13; Categoria: Luminaria del entorno · ilustrativa 13; ClaseIFC: IfcLightFixture; EstadoDeInformacion: provisional; DocumentoFuente: {"documentId":"JH-CLIENT-CONTEXT-20260909","title":"Indicación del cliente · entorno de 200 m con aparcamientos y luminarias ilustrativos","date":"2026-09-09","note":"Distribución aproximada autorizada. No acredita la posición ni el número real de plazas o farolas existentes."}; IncidenciasPendientes: ["Contexto para lectura del emplazamiento; planta derivada de cartografía, cotas y detalles simplificados. No para construcción ni mediciones de obra.","Las mediciones en el entorno expresan la geometría representada y conservan la precisión de su fuente."]; UsoDeLasMagnitudes: Entorno de coordinación: trazados derivados de las fuentes indicadas por elemento; cotas, espesores, acabados y mobiliario orientativos cuando no están documentados. No acredita propiedad, servidumbres ni cantidades de obra y no es una base de construcción.
JH_CriterioDePosicion - PosicionYEstado: {"Sistema":"ETRS89 / UTM 29N · metros","Origen del modelo":"X 729400 · Y 4301550 · Z 285 m","Alcance":"Hasta 200 m desde el lindero del proyecto; solo exterior de parcela","Planta":"Distribución ilustrativa autorizada","Altimetría":"Plano ajustado a 213 puntos XYZ de aceras, extrapolado al resto del contexto; no es un MDT levantado"}
JH_EvidenciaDeMaterial - name: Luminaria exterior · gris; status: provisional; source: Acabado visual aproximado; no especificación de proyecto.
JH_CapaBIM - IdentificadorCapa: context_furniture; NombreCapa: Entorno · aparcamientos y luminarias; Funcion: Luminaria del entorno · ilustrativa 13; VisibilidadInicial: no
JH_EntornoContexto - Estado: provisional; Origen: {"documentId":"JH-CLIENT-CONTEXT-20260909","title":"Indicación del cliente · entorno de 200 m con aparcamientos y luminarias ilustrativos","date":"2026-09-09","note":"Distribución aproximada autorizada. No acredita la posición ni el número real de plazas o farolas existentes."}; Posicion: {"Sistema":"ETRS89 / UTM 29N · metros","Origen del modelo":"X 729400 · Y 4301550 · Z 285 m","Alcance":"Hasta 200 m desde el lindero del proyecto; solo exterior de parcela","Planta":"Distribución ilustrativa autorizada","Altimetría":"Plano ajustado a 213 puntos XYZ de aceras, extrapolado al resto del contexto; no es un MDT levantado"}; DimensionesSupuestas: [{"label":"Altura de poste","value":8,"unit":"m"},{"label":"Vuelo de brazo","value":1.4,"unit":"m"}]; IncluirEnMediciones: no; EsquemaIlustrativo: yes; Criterio: Entorno de coordinación: trazados derivados de las fuentes indicadas por elemento; cotas, espesores, acabados y mobiliario orientativos cuando no están documentados. No acredita propiedad, servidumbres ni cantidades de obra y no es una base de construcción.
JH_EsquemaProvisional - Estado: No para construcción; Origen: {"documentId":"JH-CLIENT-CONTEXT-20260909","title":"Indicación del cliente · entorno de 200 m con aparcamientos y luminarias ilustrativos","date":"2026-09-09","note":"Distribución aproximada autorizada. No acredita la posición ni el número real de plazas o farolas existentes."}; DimensionesSupuestas: [{"label":"Altura de poste","value":8,"unit":"m"},{"label":"Vuelo de brazo","value":1.4,"unit":"m"}]; Posicion: {"Sistema":"ETRS89 / UTM 29N · metros","Origen del modelo":"X 729400 · Y 4301550 · Z 285 m","Alcance":"Hasta 200 m desde el lindero del proyecto; solo exterior de parcela","Planta":"Distribución ilustrativa autorizada","Altimetría":"Plano ajustado a 213 puntos XYZ de aceras, extrapolado al resto del contexto; no es un MDT levantado"}; IncluirEnMediciones: no; Criterio: {"enabled":true,"basis":"Distribución aproximada autorizada. No acredita la posición ni el número real de plazas o farolas existentes.","pending":["Posición real del mobiliario","Dimensiones y niveles definitivos"]}

# IfcLightFixture: Luminaria del entorno · ilustrativa 14
In: Parcela industrial Jinhong
Description: Entorno de coordinación: trazados derivados de las fuentes indicadas por elemento; cotas, espesores, acabados y mobiliario orientativos cuando no están documentados. No acredita propiedad, servidumbres ni cantidades de obra y no es una base de construcción.; PredefinedType: USERDEFINED; Document: Indicación del cliente · entorno de 200 m con aparcamientos y luminarias ilustrativos; Entorno de Expacio Mérida · Catastro INSPIRE, PNOA y levantamiento Berrio; Levantamiento Berrio · parcelas I-27 Vial 3 e I-18 Vial 4; IGN · ortofotografía PNOA de máxima actualidad; Group: BIM · Entorno · aparcamientos y luminarias
JH_InformacionBIM - buildingId: context; buildingName: Entorno exterior de la parcela; level: Exterior · contexto de 200 m; category: Luminaria del entorno · ilustrativa 14; ifcClass: IfcLightFixture; status: provisional; source: {"documentId":"JH-CLIENT-CONTEXT-20260909","title":"Indicación del cliente · entorno de 200 m con aparcamientos y luminarias ilustrativos","date":"2026-09-09","note":"Distribución aproximada autorizada. No acredita la posición ni el número real de plazas o farolas existentes."}; material: {"name":"Luminaria exterior · gris","status":"provisional","source":"Acabado visual aproximado; no especificación de proyecto."}; appearance: {"profileId":"ctx_light","name":"Luminaria exterior · gris","status":"criterio_visual","basis":"Acabado de contexto orientativo, sin especificación de obra."}; dimensions: {"documented":[],"assumed":[{"label":"Altura de poste","value":8,"unit":"m"},{"label":"Vuelo de brazo","value":1.4,"unit":"m"}],"geometry":[]}; classification: {"layerId":"context_furniture","layerName":"Entorno · aparcamientos y luminarias","function":"Luminaria del entorno · ilustrativa 14"}; visualLayer: {"id":"context_furniture","name":"Entorno · aparcamientos y luminarias","defaultVisible":false}; representationKind: entorno_ilustrativo; quantityEligible: no; positioning: {"Sistema":"ETRS89 / UTM 29N · metros","Origen del modelo":"X 729400 · Y 4301550 · Z 285 m","Alcance":"Hasta 200 m desde el lindero del proyecto; solo exterior de parcela","Planta":"Distribución ilustrativa autorizada","Altimetría":"Plano ajustado a 213 puntos XYZ de aceras, extrapolado al resto del contexto; no es un MDT levantado"}; issues: ["Contexto para lectura del emplazamiento; planta derivada de cartografía, cotas y detalles simplificados. No para construcción ni mediciones de obra.","Las mediciones en el entorno expresan la geometría representada y conservan la precisión de su fuente."]; conceptual: {"enabled":true,"basis":"Distribución aproximada autorizada. No acredita la posición ni el número real de plazas o farolas existentes.","pending":["Posición real del mobiliario","Dimensiones y niveles definitivos"]}; geometryMetrics: {"boundingBoxM":{"min":[-63.183342,26.215976,-0.090397],"max":[-62.477307,27.967881,8.019603]},"extentsM":[0.706035,1.751905,8.11],"meshSurfaceM2":5.532367,"meshVolumeM3":0.181319,"closedSolid":true,"basis":"Entorno de coordinación: trazados derivados de las fuentes indicadas por elemento; cotas, espesores, acabados y mobiliario orientativos cuando no están documentados. No acredita propiedad, servidumbres ni cantidades de obra y no es una base de construcción."}
JH_Trazabilidad - Origen: Indicación del cliente · entorno de 200 m con aparcamientos y luminarias ilustrativos; Estado: provisional; Capa BIM: Entorno · aparcamientos y luminarias; Mediciones de obra: Excluido; Identificador: CTX-LIGHT-14; Categoria: Luminaria del entorno · ilustrativa 14; ClaseIFC: IfcLightFixture; EstadoDeInformacion: provisional; DocumentoFuente: {"documentId":"JH-CLIENT-CONTEXT-20260909","title":"Indicación del cliente · entorno de 200 m con aparcamientos y luminarias ilustrativos","date":"2026-09-09","note":"Distribución aproximada autorizada. No acredita la posición ni el número real de plazas o farolas existentes."}; IncidenciasPendientes: ["Contexto para lectura del emplazamiento; planta derivada de cartografía, cotas y detalles simplificados. No para construcción ni mediciones de obra.","Las mediciones en el entorno expresan la geometría representada y conservan la precisión de su fuente."]; UsoDeLasMagnitudes: Entorno de coordinación: trazados derivados de las fuentes indicadas por elemento; cotas, espesores, acabados y mobiliario orientativos cuando no están documentados. No acredita propiedad, servidumbres ni cantidades de obra y no es una base de construcción.
JH_CriterioDePosicion - PosicionYEstado: {"Sistema":"ETRS89 / UTM 29N · metros","Origen del modelo":"X 729400 · Y 4301550 · Z 285 m","Alcance":"Hasta 200 m desde el lindero del proyecto; solo exterior de parcela","Planta":"Distribución ilustrativa autorizada","Altimetría":"Plano ajustado a 213 puntos XYZ de aceras, extrapolado al resto del contexto; no es un MDT levantado"}
JH_EvidenciaDeMaterial - name: Luminaria exterior · gris; status: provisional; source: Acabado visual aproximado; no especificación de proyecto.
JH_CapaBIM - IdentificadorCapa: context_furniture; NombreCapa: Entorno · aparcamientos y luminarias; Funcion: Luminaria del entorno · ilustrativa 14; VisibilidadInicial: no
JH_EntornoContexto - Estado: provisional; Origen: {"documentId":"JH-CLIENT-CONTEXT-20260909","title":"Indicación del cliente · entorno de 200 m con aparcamientos y luminarias ilustrativos","date":"2026-09-09","note":"Distribución aproximada autorizada. No acredita la posición ni el número real de plazas o farolas existentes."}; Posicion: {"Sistema":"ETRS89 / UTM 29N · metros","Origen del modelo":"X 729400 · Y 4301550 · Z 285 m","Alcance":"Hasta 200 m desde el lindero del proyecto; solo exterior de parcela","Planta":"Distribución ilustrativa autorizada","Altimetría":"Plano ajustado a 213 puntos XYZ de aceras, extrapolado al resto del contexto; no es un MDT levantado"}; DimensionesSupuestas: [{"label":"Altura de poste","value":8,"unit":"m"},{"label":"Vuelo de brazo","value":1.4,"unit":"m"}]; IncluirEnMediciones: no; EsquemaIlustrativo: yes; Criterio: Entorno de coordinación: trazados derivados de las fuentes indicadas por elemento; cotas, espesores, acabados y mobiliario orientativos cuando no están documentados. No acredita propiedad, servidumbres ni cantidades de obra y no es una base de construcción.
JH_EsquemaProvisional - Estado: No para construcción; Origen: {"documentId":"JH-CLIENT-CONTEXT-20260909","title":"Indicación del cliente · entorno de 200 m con aparcamientos y luminarias ilustrativos","date":"2026-09-09","note":"Distribución aproximada autorizada. No acredita la posición ni el número real de plazas o farolas existentes."}; DimensionesSupuestas: [{"label":"Altura de poste","value":8,"unit":"m"},{"label":"Vuelo de brazo","value":1.4,"unit":"m"}]; Posicion: {"Sistema":"ETRS89 / UTM 29N · metros","Origen del modelo":"X 729400 · Y 4301550 · Z 285 m","Alcance":"Hasta 200 m desde el lindero del proyecto; solo exterior de parcela","Planta":"Distribución ilustrativa autorizada","Altimetría":"Plano ajustado a 213 puntos XYZ de aceras, extrapolado al resto del contexto; no es un MDT levantado"}; IncluirEnMediciones: no; Criterio: {"enabled":true,"basis":"Distribución aproximada autorizada. No acredita la posición ni el número real de plazas o farolas existentes.","pending":["Posición real del mobiliario","Dimensiones y niveles definitivos"]}

# IfcLightFixture: Luminaria del entorno · ilustrativa 15
In: Parcela industrial Jinhong
Description: Entorno de coordinación: trazados derivados de las fuentes indicadas por elemento; cotas, espesores, acabados y mobiliario orientativos cuando no están documentados. No acredita propiedad, servidumbres ni cantidades de obra y no es una base de construcción.; PredefinedType: USERDEFINED; Document: Indicación del cliente · entorno de 200 m con aparcamientos y luminarias ilustrativos; Entorno de Expacio Mérida · Catastro INSPIRE, PNOA y levantamiento Berrio; Levantamiento Berrio · parcelas I-27 Vial 3 e I-18 Vial 4; IGN · ortofotografía PNOA de máxima actualidad; Group: BIM · Entorno · aparcamientos y luminarias
JH_InformacionBIM - buildingId: context; buildingName: Entorno exterior de la parcela; level: Exterior · contexto de 200 m; category: Luminaria del entorno · ilustrativa 15; ifcClass: IfcLightFixture; status: provisional; source: {"documentId":"JH-CLIENT-CONTEXT-20260909","title":"Indicación del cliente · entorno de 200 m con aparcamientos y luminarias ilustrativos","date":"2026-09-09","note":"Distribución aproximada autorizada. No acredita la posición ni el número real de plazas o farolas existentes."}; material: {"name":"Luminaria exterior · gris","status":"provisional","source":"Acabado visual aproximado; no especificación de proyecto."}; appearance: {"profileId":"ctx_light","name":"Luminaria exterior · gris","status":"criterio_visual","basis":"Acabado de contexto orientativo, sin especificación de obra."}; dimensions: {"documented":[],"assumed":[{"label":"Altura de poste","value":8,"unit":"m"},{"label":"Vuelo de brazo","value":1.4,"unit":"m"}],"geometry":[]}; classification: {"layerId":"context_furniture","layerName":"Entorno · aparcamientos y luminarias","function":"Luminaria del entorno · ilustrativa 15"}; visualLayer: {"id":"context_furniture","name":"Entorno · aparcamientos y luminarias","defaultVisible":false}; representationKind: entorno_ilustrativo; quantityEligible: no; positioning: {"Sistema":"ETRS89 / UTM 29N · metros","Origen del modelo":"X 729400 · Y 4301550 · Z 285 m","Alcance":"Hasta 200 m desde el lindero del proyecto; solo exterior de parcela","Planta":"Distribución ilustrativa autorizada","Altimetría":"Plano ajustado a 213 puntos XYZ de aceras, extrapolado al resto del contexto; no es un MDT levantado"}; issues: ["Contexto para lectura del emplazamiento; planta derivada de cartografía, cotas y detalles simplificados. No para construcción ni mediciones de obra.","Las mediciones en el entorno expresan la geometría representada y conservan la precisión de su fuente."]; conceptual: {"enabled":true,"basis":"Distribución aproximada autorizada. No acredita la posición ni el número real de plazas o farolas existentes.","pending":["Posición real del mobiliario","Dimensiones y niveles definitivos"]}; geometryMetrics: {"boundingBoxM":{"min":[123.524342,-25.923981,1.887315],"max":[124.230377,-24.172076,9.997315]},"extentsM":[0.706035,1.751905,8.11],"meshSurfaceM2":5.532364,"meshVolumeM3":0.181319,"closedSolid":true,"basis":"Entorno de coordinación: trazados derivados de las fuentes indicadas por elemento; cotas, espesores, acabados y mobiliario orientativos cuando no están documentados. No acredita propiedad, servidumbres ni cantidades de obra y no es una base de construcción."}
JH_Trazabilidad - Origen: Indicación del cliente · entorno de 200 m con aparcamientos y luminarias ilustrativos; Estado: provisional; Capa BIM: Entorno · aparcamientos y luminarias; Mediciones de obra: Excluido; Identificador: CTX-LIGHT-15; Categoria: Luminaria del entorno · ilustrativa 15; ClaseIFC: IfcLightFixture; EstadoDeInformacion: provisional; DocumentoFuente: {"documentId":"JH-CLIENT-CONTEXT-20260909","title":"Indicación del cliente · entorno de 200 m con aparcamientos y luminarias ilustrativos","date":"2026-09-09","note":"Distribución aproximada autorizada. No acredita la posición ni el número real de plazas o farolas existentes."}; IncidenciasPendientes: ["Contexto para lectura del emplazamiento; planta derivada de cartografía, cotas y detalles simplificados. No para construcción ni mediciones de obra.","Las mediciones en el entorno expresan la geometría representada y conservan la precisión de su fuente."]; UsoDeLasMagnitudes: Entorno de coordinación: trazados derivados de las fuentes indicadas por elemento; cotas, espesores, acabados y mobiliario orientativos cuando no están documentados. No acredita propiedad, servidumbres ni cantidades de obra y no es una base de construcción.
JH_CriterioDePosicion - PosicionYEstado: {"Sistema":"ETRS89 / UTM 29N · metros","Origen del modelo":"X 729400 · Y 4301550 · Z 285 m","Alcance":"Hasta 200 m desde el lindero del proyecto; solo exterior de parcela","Planta":"Distribución ilustrativa autorizada","Altimetría":"Plano ajustado a 213 puntos XYZ de aceras, extrapolado al resto del contexto; no es un MDT levantado"}
JH_EvidenciaDeMaterial - name: Luminaria exterior · gris; status: provisional; source: Acabado visual aproximado; no especificación de proyecto.
JH_CapaBIM - IdentificadorCapa: context_furniture; NombreCapa: Entorno · aparcamientos y luminarias; Funcion: Luminaria del entorno · ilustrativa 15; VisibilidadInicial: no
JH_EntornoContexto - Estado: provisional; Origen: {"documentId":"JH-CLIENT-CONTEXT-20260909","title":"Indicación del cliente · entorno de 200 m con aparcamientos y luminarias ilustrativos","date":"2026-09-09","note":"Distribución aproximada autorizada. No acredita la posición ni el número real de plazas o farolas existentes."}; Posicion: {"Sistema":"ETRS89 / UTM 29N · metros","Origen del modelo":"X 729400 · Y 4301550 · Z 285 m","Alcance":"Hasta 200 m desde el lindero del proyecto; solo exterior de parcela","Planta":"Distribución ilustrativa autorizada","Altimetría":"Plano ajustado a 213 puntos XYZ de aceras, extrapolado al resto del contexto; no es un MDT levantado"}; DimensionesSupuestas: [{"label":"Altura de poste","value":8,"unit":"m"},{"label":"Vuelo de brazo","value":1.4,"unit":"m"}]; IncluirEnMediciones: no; EsquemaIlustrativo: yes; Criterio: Entorno de coordinación: trazados derivados de las fuentes indicadas por elemento; cotas, espesores, acabados y mobiliario orientativos cuando no están documentados. No acredita propiedad, servidumbres ni cantidades de obra y no es una base de construcción.
JH_EsquemaProvisional - Estado: No para construcción; Origen: {"documentId":"JH-CLIENT-CONTEXT-20260909","title":"Indicación del cliente · entorno de 200 m con aparcamientos y luminarias ilustrativos","date":"2026-09-09","note":"Distribución aproximada autorizada. No acredita la posición ni el número real de plazas o farolas existentes."}; DimensionesSupuestas: [{"label":"Altura de poste","value":8,"unit":"m"},{"label":"Vuelo de brazo","value":1.4,"unit":"m"}]; Posicion: {"Sistema":"ETRS89 / UTM 29N · metros","Origen del modelo":"X 729400 · Y 4301550 · Z 285 m","Alcance":"Hasta 200 m desde el lindero del proyecto; solo exterior de parcela","Planta":"Distribución ilustrativa autorizada","Altimetría":"Plano ajustado a 213 puntos XYZ de aceras, extrapolado al resto del contexto; no es un MDT levantado"}; IncluirEnMediciones: no; Criterio: {"enabled":true,"basis":"Distribución aproximada autorizada. No acredita la posición ni el número real de plazas o farolas existentes.","pending":["Posición real del mobiliario","Dimensiones y niveles definitivos"]}

# IfcLightFixture: Luminaria del entorno · ilustrativa 16
In: Parcela industrial Jinhong
Description: Entorno de coordinación: trazados derivados de las fuentes indicadas por elemento; cotas, espesores, acabados y mobiliario orientativos cuando no están documentados. No acredita propiedad, servidumbres ni cantidades de obra y no es una base de construcción.; PredefinedType: USERDEFINED; Document: Indicación del cliente · entorno de 200 m con aparcamientos y luminarias ilustrativos; Entorno de Expacio Mérida · Catastro INSPIRE, PNOA y levantamiento Berrio; Levantamiento Berrio · parcelas I-27 Vial 3 e I-18 Vial 4; IGN · ortofotografía PNOA de máxima actualidad; Group: BIM · Entorno · aparcamientos y luminarias
JH_InformacionBIM - buildingId: context; buildingName: Entorno exterior de la parcela; level: Exterior · contexto de 200 m; category: Luminaria del entorno · ilustrativa 16; ifcClass: IfcLightFixture; status: provisional; source: {"documentId":"JH-CLIENT-CONTEXT-20260909","title":"Indicación del cliente · entorno de 200 m con aparcamientos y luminarias ilustrativos","date":"2026-09-09","note":"Distribución aproximada autorizada. No acredita la posición ni el número real de plazas o farolas existentes."}; material: {"name":"Luminaria exterior · gris","status":"provisional","source":"Acabado visual aproximado; no especificación de proyecto."}; appearance: {"profileId":"ctx_light","name":"Luminaria exterior · gris","status":"criterio_visual","basis":"Acabado de contexto orientativo, sin especificación de obra."}; dimensions: {"documented":[],"assumed":[{"label":"Altura de poste","value":8,"unit":"m"},{"label":"Vuelo de brazo","value":1.4,"unit":"m"}],"geometry":[]}; classification: {"layerId":"context_furniture","layerName":"Entorno · aparcamientos y luminarias","function":"Luminaria del entorno · ilustrativa 16"}; visualLayer: {"id":"context_furniture","name":"Entorno · aparcamientos y luminarias","defaultVisible":false}; representationKind: entorno_ilustrativo; quantityEligible: no; positioning: {"Sistema":"ETRS89 / UTM 29N · metros","Origen del modelo":"X 729400 · Y 4301550 · Z 285 m","Alcance":"Hasta 200 m desde el lindero del proyecto; solo exterior de parcela","Planta":"Distribución ilustrativa autorizada","Altimetría":"Plano ajustado a 213 puntos XYZ de aceras, extrapolado al resto del contexto; no es un MDT levantado"}; issues: ["Contexto para lectura del emplazamiento; planta derivada de cartografía, cotas y detalles simplificados. No para construcción ni mediciones de obra.","Las mediciones en el entorno expresan la geometría representada y conservan la precisión de su fuente."]; conceptual: {"enabled":true,"basis":"Distribución aproximada autorizada. No acredita la posición ni el número real de plazas o farolas existentes.","pending":["Posición real del mobiliario","Dimensiones y niveles definitivos"]}; geometryMetrics: {"boundingBoxM":{"min":[158.857921,-3.358976,2.355719],"max":[159.563956,-1.60707,10.465719]},"extentsM":[0.706035,1.751906,8.11],"meshSurfaceM2":5.532362,"meshVolumeM3":0.181319,"closedSolid":true,"basis":"Entorno de coordinación: trazados derivados de las fuentes indicadas por elemento; cotas, espesores, acabados y mobiliario orientativos cuando no están documentados. No acredita propiedad, servidumbres ni cantidades de obra y no es una base de construcción."}
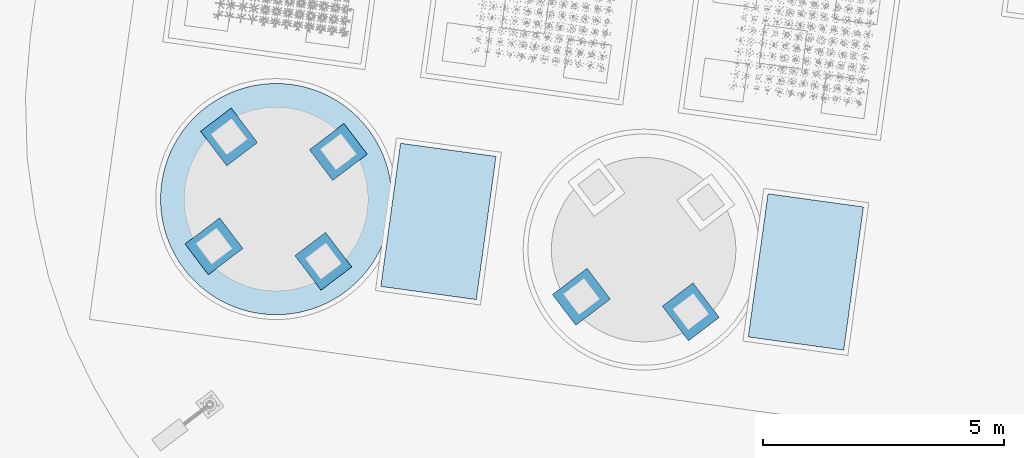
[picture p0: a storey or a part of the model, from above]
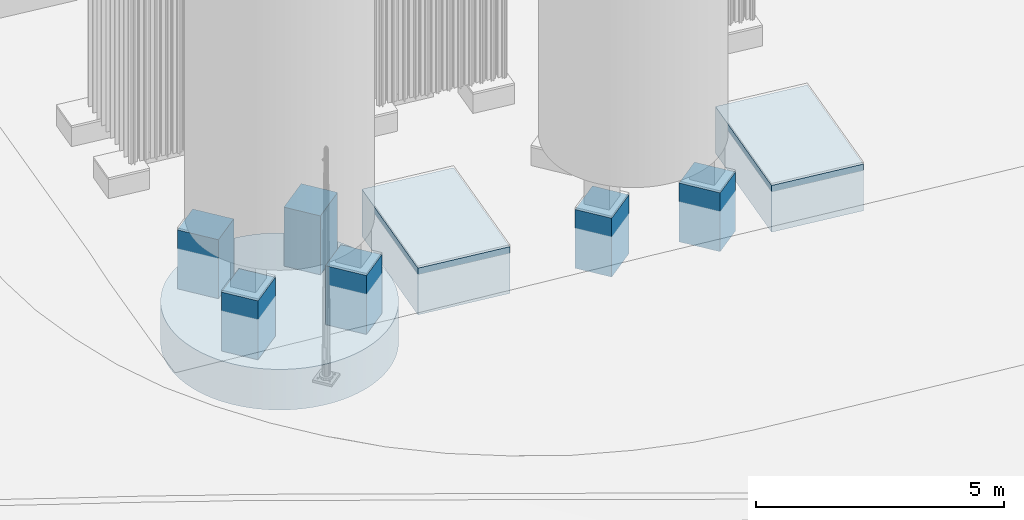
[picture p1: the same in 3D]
Properties of the parts of a building model (IFC4), part 91 of 134

# IfcLightFixture: Luminaria del entorno · ilustrativa 16
JH_Trazabilidad - Origen: Indicación del cliente · entorno de 200 m con aparcamientos y luminarias ilustrativos; Estado: provisional; Capa BIM: Entorno · aparcamientos y luminarias; Mediciones de obra: Excluido; Identificador: CTX-LIGHT-16; Categoria: Luminaria del entorno · ilustrativa 16; ClaseIFC: IfcLightFixture; EstadoDeInformacion: provisional; DocumentoFuente: {"documentId":"JH-CLIENT-CONTEXT-20260909","title":"Indicación del cliente · entorno de 200 m con aparcamientos y luminarias ilustrativos","date":"2026-09-09","note":"Distribución aproximada autorizada. No acredita la posición ni el número real de plazas o farolas existentes."}; IncidenciasPendientes: ["Contexto para lectura del emplazamiento; planta derivada de cartografía, cotas y detalles simplificados. No para construcción ni mediciones de obra.","Las mediciones en el entorno expresan la geometría representada y conservan la precisión de su fuente."]; UsoDeLasMagnitudes: Entorno de coordinación: trazados derivados de las fuentes indicadas por elemento; cotas, espesores, acabados y mobiliario orientativos cuando no están documentados. No acredita propiedad, servidumbres ni cantidades de obra y no es una base de construcción.
JH_CriterioDePosicion - PosicionYEstado: {"Sistema":"ETRS89 / UTM 29N · metros","Origen del modelo":"X 729400 · Y 4301550 · Z 285 m","Alcance":"Hasta 200 m desde el lindero del proyecto; solo exterior de parcela","Planta":"Distribución ilustrativa autorizada","Altimetría":"Plano ajustado a 213 puntos XYZ de aceras, extrapolado al resto del contexto; no es un MDT levantado"}
JH_EvidenciaDeMaterial - name: Luminaria exterior · gris; status: provisional; source: Acabado visual aproximado; no especificación de proyecto.
JH_CapaBIM - IdentificadorCapa: context_furniture; NombreCapa: Entorno · aparcamientos y luminarias; Funcion: Luminaria del entorno · ilustrativa 16; VisibilidadInicial: no
JH_EntornoContexto - Estado: provisional; Origen: {"documentId":"JH-CLIENT-CONTEXT-20260909","title":"Indicación del cliente · entorno de 200 m con aparcamientos y luminarias ilustrativos","date":"2026-09-09","note":"Distribución aproximada autorizada. No acredita la posición ni el número real de plazas o farolas existentes."}; Posicion: {"Sistema":"ETRS89 / UTM 29N · metros","Origen del modelo":"X 729400 · Y 4301550 · Z 285 m","Alcance":"Hasta 200 m desde el lindero del proyecto; solo exterior de parcela","Planta":"Distribución ilustrativa autorizada","Altimetría":"Plano ajustado a 213 puntos XYZ de aceras, extrapolado al resto del contexto; no es un MDT levantado"}; DimensionesSupuestas: [{"label":"Altura de poste","value":8,"unit":"m"},{"label":"Vuelo de brazo","value":1.4,"unit":"m"}]; IncluirEnMediciones: no; EsquemaIlustrativo: yes; Criterio: Entorno de coordinación: trazados derivados de las fuentes indicadas por elemento; cotas, espesores, acabados y mobiliario orientativos cuando no están documentados. No acredita propiedad, servidumbres ni cantidades de obra y no es una base de construcción.
JH_EsquemaProvisional - Estado: No para construcción; Origen: {"documentId":"JH-CLIENT-CONTEXT-20260909","title":"Indicación del cliente · entorno de 200 m con aparcamientos y luminarias ilustrativos","date":"2026-09-09","note":"Distribución aproximada autorizada. No acredita la posición ni el número real de plazas o farolas existentes."}; DimensionesSupuestas: [{"label":"Altura de poste","value":8,"unit":"m"},{"label":"Vuelo de brazo","value":1.4,"unit":"m"}]; Posicion: {"Sistema":"ETRS89 / UTM 29N · metros","Origen del modelo":"X 729400 · Y 4301550 · Z 285 m","Alcance":"Hasta 200 m desde el lindero del proyecto; solo exterior de parcela","Planta":"Distribución ilustrativa autorizada","Altimetría":"Plano ajustado a 213 puntos XYZ de aceras, extrapolado al resto del contexto; no es un MDT levantado"}; IncluirEnMediciones: no; Criterio: {"enabled":true,"basis":"Distribución aproximada autorizada. No acredita la posición ni el número real de plazas o farolas existentes.","pending":["Posición real del mobiliario","Dimensiones y niveles definitivos"]}

# IfcLightFixture: Luminaria del entorno · ilustrativa 17
In: Parcela industrial Jinhong
Description: Entorno de coordinación: trazados derivados de las fuentes indicadas por elemento; cotas, espesores, acabados y mobiliario orientativos cuando no están documentados. No acredita propiedad, servidumbres ni cantidades de obra y no es una base de construcción.; PredefinedType: USERDEFINED; Document: Indicación del cliente · entorno de 200 m con aparcamientos y luminarias ilustrativos; Entorno de Expacio Mérida · Catastro INSPIRE, PNOA y levantamiento Berrio; Levantamiento Berrio · parcelas I-27 Vial 3 e I-18 Vial 4; IGN · ortofotografía PNOA de máxima actualidad; Group: BIM · Entorno · aparcamientos y luminarias
JH_InformacionBIM - buildingId: context; buildingName: Entorno exterior de la parcela; level: Exterior · contexto de 200 m; category: Luminaria del entorno · ilustrativa 17; ifcClass: IfcLightFixture; status: provisional; source: {"documentId":"JH-CLIENT-CONTEXT-20260909","title":"Indicación del cliente · entorno de 200 m con aparcamientos y luminarias ilustrativos","date":"2026-09-09","note":"Distribución aproximada autorizada. No acredita la posición ni el número real de plazas o farolas existentes."}; material: {"name":"Luminaria exterior · gris","status":"provisional","source":"Acabado visual aproximado; no especificación de proyecto."}; appearance: {"profileId":"ctx_light","name":"Luminaria exterior · gris","status":"criterio_visual","basis":"Acabado de contexto orientativo, sin especificación de obra."}; dimensions: {"documented":[],"assumed":[{"label":"Altura de poste","value":8,"unit":"m"},{"label":"Vuelo de brazo","value":1.4,"unit":"m"}],"geometry":[]}; classification: {"layerId":"context_furniture","layerName":"Entorno · aparcamientos y luminarias","function":"Luminaria del entorno · ilustrativa 17"}; visualLayer: {"id":"context_furniture","name":"Entorno · aparcamientos y luminarias","defaultVisible":false}; representationKind: entorno_ilustrativo; quantityEligible: no; positioning: {"Sistema":"ETRS89 / UTM 29N · metros","Origen del modelo":"X 729400 · Y 4301550 · Z 285 m","Alcance":"Hasta 200 m desde el lindero del proyecto; solo exterior de parcela","Planta":"Distribución ilustrativa autorizada","Altimetría":"Plano ajustado a 213 puntos XYZ de aceras, extrapolado al resto del contexto; no es un MDT levantado"}; issues: ["Contexto para lectura del emplazamiento; planta derivada de cartografía, cotas y detalles simplificados. No para construcción ni mediciones de obra.","Las mediciones en el entorno expresan la geometría representada y conservan la precisión de su fuente."]; conceptual: {"enabled":true,"basis":"Distribución aproximada autorizada. No acredita la posición ni el número real de plazas o farolas existentes.","pending":["Posición real del mobiliario","Dimensiones y niveles definitivos"]}; geometryMetrics: {"boundingBoxM":{"min":[190.558608,-7.72549,2.704565],"max":[191.264643,-5.973584,10.814565]},"extentsM":[0.706035,1.751906,8.11],"meshSurfaceM2":5.532363,"meshVolumeM3":0.181319,"closedSolid":true,"basis":"Entorno de coordinación: trazados derivados de las fuentes indicadas por elemento; cotas, espesores, acabados y mobiliario orientativos cuando no están documentados. No acredita propiedad, servidumbres ni cantidades de obra y no es una base de construcción."}
JH_Trazabilidad - Origen: Indicación del cliente · entorno de 200 m con aparcamientos y luminarias ilustrativos; Estado: provisional; Capa BIM: Entorno · aparcamientos y luminarias; Mediciones de obra: Excluido; Identificador: CTX-LIGHT-17; Categoria: Luminaria del entorno · ilustrativa 17; ClaseIFC: IfcLightFixture; EstadoDeInformacion: provisional; DocumentoFuente: {"documentId":"JH-CLIENT-CONTEXT-20260909","title":"Indicación del cliente · entorno de 200 m con aparcamientos y luminarias ilustrativos","date":"2026-09-09","note":"Distribución aproximada autorizada. No acredita la posición ni el número real de plazas o farolas existentes."}; IncidenciasPendientes: ["Contexto para lectura del emplazamiento; planta derivada de cartografía, cotas y detalles simplificados. No para construcción ni mediciones de obra.","Las mediciones en el entorno expresan la geometría representada y conservan la precisión de su fuente."]; UsoDeLasMagnitudes: Entorno de coordinación: trazados derivados de las fuentes indicadas por elemento; cotas, espesores, acabados y mobiliario orientativos cuando no están documentados. No acredita propiedad, servidumbres ni cantidades de obra y no es una base de construcción.
JH_CriterioDePosicion - PosicionYEstado: {"Sistema":"ETRS89 / UTM 29N · metros","Origen del modelo":"X 729400 · Y 4301550 · Z 285 m","Alcance":"Hasta 200 m desde el lindero del proyecto; solo exterior de parcela","Planta":"Distribución ilustrativa autorizada","Altimetría":"Plano ajustado a 213 puntos XYZ de aceras, extrapolado al resto del contexto; no es un MDT levantado"}
JH_EvidenciaDeMaterial - name: Luminaria exterior · gris; status: provisional; source: Acabado visual aproximado; no especificación de proyecto.
JH_CapaBIM - IdentificadorCapa: context_furniture; NombreCapa: Entorno · aparcamientos y luminarias; Funcion: Luminaria del entorno · ilustrativa 17; VisibilidadInicial: no
JH_EntornoContexto - Estado: provisional; Origen: {"documentId":"JH-CLIENT-CONTEXT-20260909","title":"Indicación del cliente · entorno de 200 m con aparcamientos y luminarias ilustrativos","date":"2026-09-09","note":"Distribución aproximada autorizada. No acredita la posición ni el número real de plazas o farolas existentes."}; Posicion: {"Sistema":"ETRS89 / UTM 29N · metros","Origen del modelo":"X 729400 · Y 4301550 · Z 285 m","Alcance":"Hasta 200 m desde el lindero del proyecto; solo exterior de parcela","Planta":"Distribución ilustrativa autorizada","Altimetría":"Plano ajustado a 213 puntos XYZ de aceras, extrapolado al resto del contexto; no es un MDT levantado"}; DimensionesSupuestas: [{"label":"Altura de poste","value":8,"unit":"m"},{"label":"Vuelo de brazo","value":1.4,"unit":"m"}]; IncluirEnMediciones: no; EsquemaIlustrativo: yes; Criterio: Entorno de coordinación: trazados derivados de las fuentes indicadas por elemento; cotas, espesores, acabados y mobiliario orientativos cuando no están documentados. No acredita propiedad, servidumbres ni cantidades de obra y no es una base de construcción.
JH_EsquemaProvisional - Estado: No para construcción; Origen: {"documentId":"JH-CLIENT-CONTEXT-20260909","title":"Indicación del cliente · entorno de 200 m con aparcamientos y luminarias ilustrativos","date":"2026-09-09","note":"Distribución aproximada autorizada. No acredita la posición ni el número real de plazas o farolas existentes."}; DimensionesSupuestas: [{"label":"Altura de poste","value":8,"unit":"m"},{"label":"Vuelo de brazo","value":1.4,"unit":"m"}]; Posicion: {"Sistema":"ETRS89 / UTM 29N · metros","Origen del modelo":"X 729400 · Y 4301550 · Z 285 m","Alcance":"Hasta 200 m desde el lindero del proyecto; solo exterior de parcela","Planta":"Distribución ilustrativa autorizada","Altimetría":"Plano ajustado a 213 puntos XYZ de aceras, extrapolado al resto del contexto; no es un MDT levantado"}; IncluirEnMediciones: no; Criterio: {"enabled":true,"basis":"Distribución aproximada autorizada. No acredita la posición ni el número real de plazas o farolas existentes.","pending":["Posición real del mobiliario","Dimensiones y niveles definitivos"]}

# IfcLightFixture: Luminaria del entorno · ilustrativa 18
In: Parcela industrial Jinhong
Description: Entorno de coordinación: trazados derivados de las fuentes indicadas por elemento; cotas, espesores, acabados y mobiliario orientativos cuando no están documentados. No acredita propiedad, servidumbres ni cantidades de obra y no es una base de construcción.; PredefinedType: USERDEFINED; Document: Indicación del cliente · entorno de 200 m con aparcamientos y luminarias ilustrativos; Entorno de Expacio Mérida · Catastro INSPIRE, PNOA y levantamiento Berrio; Levantamiento Berrio · parcelas I-27 Vial 3 e I-18 Vial 4; IGN · ortofotografía PNOA de máxima actualidad; Group: BIM · Entorno · aparcamientos y luminarias
JH_InformacionBIM - buildingId: context; buildingName: Entorno exterior de la parcela; level: Exterior · contexto de 200 m; category: Luminaria del entorno · ilustrativa 18; ifcClass: IfcLightFixture; status: provisional; source: {"documentId":"JH-CLIENT-CONTEXT-20260909","title":"Indicación del cliente · entorno de 200 m con aparcamientos y luminarias ilustrativos","date":"2026-09-09","note":"Distribución aproximada autorizada. No acredita la posición ni el número real de plazas o farolas existentes."}; material: {"name":"Luminaria exterior · gris","status":"provisional","source":"Acabado visual aproximado; no especificación de proyecto."}; appearance: {"profileId":"ctx_light","name":"Luminaria exterior · gris","status":"criterio_visual","basis":"Acabado de contexto orientativo, sin especificación de obra."}; dimensions: {"documented":[],"assumed":[{"label":"Altura de poste","value":8,"unit":"m"},{"label":"Vuelo de brazo","value":1.4,"unit":"m"}],"geometry":[]}; classification: {"layerId":"context_furniture","layerName":"Entorno · aparcamientos y luminarias","function":"Luminaria del entorno · ilustrativa 18"}; visualLayer: {"id":"context_furniture","name":"Entorno · aparcamientos y luminarias","defaultVisible":false}; representationKind: entorno_ilustrativo; quantityEligible: no; positioning: {"Sistema":"ETRS89 / UTM 29N · metros","Origen del modelo":"X 729400 · Y 4301550 · Z 285 m","Alcance":"Hasta 200 m desde el lindero del proyecto; solo exterior de parcela","Planta":"Distribución ilustrativa autorizada","Altimetría":"Plano ajustado a 213 puntos XYZ de aceras, extrapolado al resto del contexto; no es un MDT levantado"}; issues: ["Contexto para lectura del emplazamiento; planta derivada de cartografía, cotas y detalles simplificados. No para construcción ni mediciones de obra.","Las mediciones en el entorno expresan la geometría representada y conservan la precisión de su fuente."]; conceptual: {"enabled":true,"basis":"Distribución aproximada autorizada. No acredita la posición ni el número real de plazas o farolas existentes.","pending":["Posición real del mobiliario","Dimensiones y niveles definitivos"]}; geometryMetrics: {"boundingBoxM":{"min":[222.327521,-11.59668,3.055508],"max":[223.033556,-9.844775,11.165508]},"extentsM":[0.706035,1.751905,8.11],"meshSurfaceM2":5.532365,"meshVolumeM3":0.181319,"closedSolid":true,"basis":"Entorno de coordinación: trazados derivados de las fuentes indicadas por elemento; cotas, espesores, acabados y mobiliario orientativos cuando no están documentados. No acredita propiedad, servidumbres ni cantidades de obra y no es una base de construcción."}
JH_Trazabilidad - Origen: Indicación del cliente · entorno de 200 m con aparcamientos y luminarias ilustrativos; Estado: provisional; Capa BIM: Entorno · aparcamientos y luminarias; Mediciones de obra: Excluido; Identificador: CTX-LIGHT-18; Categoria: Luminaria del entorno · ilustrativa 18; ClaseIFC: IfcLightFixture; EstadoDeInformacion: provisional; DocumentoFuente: {"documentId":"JH-CLIENT-CONTEXT-20260909","title":"Indicación del cliente · entorno de 200 m con aparcamientos y luminarias ilustrativos","date":"2026-09-09","note":"Distribución aproximada autorizada. No acredita la posición ni el número real de plazas o farolas existentes."}; IncidenciasPendientes: ["Contexto para lectura del emplazamiento; planta derivada de cartografía, cotas y detalles simplificados. No para construcción ni mediciones de obra.","Las mediciones en el entorno expresan la geometría representada y conservan la precisión de su fuente."]; UsoDeLasMagnitudes: Entorno de coordinación: trazados derivados de las fuentes indicadas por elemento; cotas, espesores, acabados y mobiliario orientativos cuando no están documentados. No acredita propiedad, servidumbres ni cantidades de obra y no es una base de construcción.
JH_CriterioDePosicion - PosicionYEstado: {"Sistema":"ETRS89 / UTM 29N · metros","Origen del modelo":"X 729400 · Y 4301550 · Z 285 m","Alcance":"Hasta 200 m desde el lindero del proyecto; solo exterior de parcela","Planta":"Distribución ilustrativa autorizada","Altimetría":"Plano ajustado a 213 puntos XYZ de aceras, extrapolado al resto del contexto; no es un MDT levantado"}
JH_EvidenciaDeMaterial - name: Luminaria exterior · gris; status: provisional; source: Acabado visual aproximado; no especificación de proyecto.
JH_CapaBIM - IdentificadorCapa: context_furniture; NombreCapa: Entorno · aparcamientos y luminarias; Funcion: Luminaria del entorno · ilustrativa 18; VisibilidadInicial: no
JH_EntornoContexto - Estado: provisional; Origen: {"documentId":"JH-CLIENT-CONTEXT-20260909","title":"Indicación del cliente · entorno de 200 m con aparcamientos y luminarias ilustrativos","date":"2026-09-09","note":"Distribución aproximada autorizada. No acredita la posición ni el número real de plazas o farolas existentes."}; Posicion: {"Sistema":"ETRS89 / UTM 29N · metros","Origen del modelo":"X 729400 · Y 4301550 · Z 285 m","Alcance":"Hasta 200 m desde el lindero del proyecto; solo exterior de parcela","Planta":"Distribución ilustrativa autorizada","Altimetría":"Plano ajustado a 213 puntos XYZ de aceras, extrapolado al resto del contexto; no es un MDT levantado"}; DimensionesSupuestas: [{"label":"Altura de poste","value":8,"unit":"m"},{"label":"Vuelo de brazo","value":1.4,"unit":"m"}]; IncluirEnMediciones: no; EsquemaIlustrativo: yes; Criterio: Entorno de coordinación: trazados derivados de las fuentes indicadas por elemento; cotas, espesores, acabados y mobiliario orientativos cuando no están documentados. No acredita propiedad, servidumbres ni cantidades de obra y no es una base de construcción.
JH_EsquemaProvisional - Estado: No para construcción; Origen: {"documentId":"JH-CLIENT-CONTEXT-20260909","title":"Indicación del cliente · entorno de 200 m con aparcamientos y luminarias ilustrativos","date":"2026-09-09","note":"Distribución aproximada autorizada. No acredita la posición ni el número real de plazas o farolas existentes."}; DimensionesSupuestas: [{"label":"Altura de poste","value":8,"unit":"m"},{"label":"Vuelo de brazo","value":1.4,"unit":"m"}]; Posicion: {"Sistema":"ETRS89 / UTM 29N · metros","Origen del modelo":"X 729400 · Y 4301550 · Z 285 m","Alcance":"Hasta 200 m desde el lindero del proyecto; solo exterior de parcela","Planta":"Distribución ilustrativa autorizada","Altimetría":"Plano ajustado a 213 puntos XYZ de aceras, extrapolado al resto del contexto; no es un MDT levantado"}; IncluirEnMediciones: no; Criterio: {"enabled":true,"basis":"Distribución aproximada autorizada. No acredita la posición ni el número real de plazas o farolas existentes.","pending":["Posición real del mobiliario","Dimensiones y niveles definitivos"]}

# IfcLightFixture: Luminaria del entorno · ilustrativa 19
In: Parcela industrial Jinhong
Description: Entorno de coordinación: trazados derivados de las fuentes indicadas por elemento; cotas, espesores, acabados y mobiliario orientativos cuando no están documentados. No acredita propiedad, servidumbres ni cantidades de obra y no es una base de construcción.; PredefinedType: USERDEFINED; Document: Indicación del cliente · entorno de 200 m con aparcamientos y luminarias ilustrativos; Entorno de Expacio Mérida · Catastro INSPIRE, PNOA y levantamiento Berrio; Levantamiento Berrio · parcelas I-27 Vial 3 e I-18 Vial 4; IGN · ortofotografía PNOA de máxima actualidad; Group: BIM · Entorno · aparcamientos y luminarias
JH_InformacionBIM - buildingId: context; buildingName: Entorno exterior de la parcela; level: Exterior · contexto de 200 m; category: Luminaria del entorno · ilustrativa 19; ifcClass: IfcLightFixture; status: provisional; source: {"documentId":"JH-CLIENT-CONTEXT-20260909","title":"Indicación del cliente · entorno de 200 m con aparcamientos y luminarias ilustrativos","date":"2026-09-09","note":"Distribución aproximada autorizada. No acredita la posición ni el número real de plazas o farolas existentes."}; material: {"name":"Luminaria exterior · gris","status":"provisional","source":"Acabado visual aproximado; no especificación de proyecto."}; appearance: {"profileId":"ctx_light","name":"Luminaria exterior · gris","status":"criterio_visual","basis":"Acabado de contexto orientativo, sin especificación de obra."}; dimensions: {"documented":[],"assumed":[{"label":"Altura de poste","value":8,"unit":"m"},{"label":"Vuelo de brazo","value":1.4,"unit":"m"}],"geometry":[]}; classification: {"layerId":"context_furniture","layerName":"Entorno · aparcamientos y luminarias","function":"Luminaria del entorno · ilustrativa 19"}; visualLayer: {"id":"context_furniture","name":"Entorno · aparcamientos y luminarias","defaultVisible":false}; representationKind: entorno_ilustrativo; quantityEligible: no; positioning: {"Sistema":"ETRS89 / UTM 29N · metros","Origen del modelo":"X 729400 · Y 4301550 · Z 285 m","Alcance":"Hasta 200 m desde el lindero del proyecto; solo exterior de parcela","Planta":"Distribución ilustrativa autorizada","Altimetría":"Plano ajustado a 213 puntos XYZ de aceras, extrapolado al resto del contexto; no es un MDT levantado"}; issues: ["Contexto para lectura del emplazamiento; planta derivada de cartografía, cotas y detalles simplificados. No para construcción ni mediciones de obra.","Las mediciones en el entorno expresan la geometría representada y conservan la precisión de su fuente."]; conceptual: {"enabled":true,"basis":"Distribución aproximada autorizada. No acredita la posición ni el número real de plazas o farolas existentes.","pending":["Posición real del mobiliario","Dimensiones y niveles definitivos"]}; geometryMetrics: {"boundingBoxM":{"min":[250.190636,-44.380683,3.278503],"max":[250.896671,-42.628778,11.388503]},"extentsM":[0.706035,1.751905,8.11],"meshSurfaceM2":5.532362,"meshVolumeM3":0.181319,"closedSolid":true,"basis":"Entorno de coordinación: trazados derivados de las fuentes indicadas por elemento; cotas, espesores, acabados y mobiliario orientativos cuando no están documentados. No acredita propiedad, servidumbres ni cantidades de obra y no es una base de construcción."}
JH_Trazabilidad - Origen: Indicación del cliente · entorno de 200 m con aparcamientos y luminarias ilustrativos; Estado: provisional; Capa BIM: Entorno · aparcamientos y luminarias; Mediciones de obra: Excluido; Identificador: CTX-LIGHT-19; Categoria: Luminaria del entorno · ilustrativa 19; ClaseIFC: IfcLightFixture; EstadoDeInformacion: provisional; DocumentoFuente: {"documentId":"JH-CLIENT-CONTEXT-20260909","title":"Indicación del cliente · entorno de 200 m con aparcamientos y luminarias ilustrativos","date":"2026-09-09","note":"Distribución aproximada autorizada. No acredita la posición ni el número real de plazas o farolas existentes."}; IncidenciasPendientes: ["Contexto para lectura del emplazamiento; planta derivada de cartografía, cotas y detalles simplificados. No para construcción ni mediciones de obra.","Las mediciones en el entorno expresan la geometría representada y conservan la precisión de su fuente."]; UsoDeLasMagnitudes: Entorno de coordinación: trazados derivados de las fuentes indicadas por elemento; cotas, espesores, acabados y mobiliario orientativos cuando no están documentados. No acredita propiedad, servidumbres ni cantidades de obra y no es una base de construcción.
JH_CriterioDePosicion - PosicionYEstado: {"Sistema":"ETRS89 / UTM 29N · metros","Origen del modelo":"X 729400 · Y 4301550 · Z 285 m","Alcance":"Hasta 200 m desde el lindero del proyecto; solo exterior de parcela","Planta":"Distribución ilustrativa autorizada","Altimetría":"Plano ajustado a 213 puntos XYZ de aceras, extrapolado al resto del contexto; no es un MDT levantado"}
JH_EvidenciaDeMaterial - name: Luminaria exterior · gris; status: provisional; source: Acabado visual aproximado; no especificación de proyecto.
JH_CapaBIM - IdentificadorCapa: context_furniture; NombreCapa: Entorno · aparcamientos y luminarias; Funcion: Luminaria del entorno · ilustrativa 19; VisibilidadInicial: no
JH_EntornoContexto - Estado: provisional; Origen: {"documentId":"JH-CLIENT-CONTEXT-20260909","title":"Indicación del cliente · entorno de 200 m con aparcamientos y luminarias ilustrativos","date":"2026-09-09","note":"Distribución aproximada autorizada. No acredita la posición ni el número real de plazas o farolas existentes."}; Posicion: {"Sistema":"ETRS89 / UTM 29N · metros","Origen del modelo":"X 729400 · Y 4301550 · Z 285 m","Alcance":"Hasta 200 m desde el lindero del proyecto; solo exterior de parcela","Planta":"Distribución ilustrativa autorizada","Altimetría":"Plano ajustado a 213 puntos XYZ de aceras, extrapolado al resto del contexto; no es un MDT levantado"}; DimensionesSupuestas: [{"label":"Altura de poste","value":8,"unit":"m"},{"label":"Vuelo de brazo","value":1.4,"unit":"m"}]; IncluirEnMediciones: no; EsquemaIlustrativo: yes; Criterio: Entorno de coordinación: trazados derivados de las fuentes indicadas por elemento; cotas, espesores, acabados y mobiliario orientativos cuando no están documentados. No acredita propiedad, servidumbres ni cantidades de obra y no es una base de construcción.
JH_EsquemaProvisional - Estado: No para construcción; Origen: {"documentId":"JH-CLIENT-CONTEXT-20260909","title":"Indicación del cliente · entorno de 200 m con aparcamientos y luminarias ilustrativos","date":"2026-09-09","note":"Distribución aproximada autorizada. No acredita la posición ni el número real de plazas o farolas existentes."}; DimensionesSupuestas: [{"label":"Altura de poste","value":8,"unit":"m"},{"label":"Vuelo de brazo","value":1.4,"unit":"m"}]; Posicion: {"Sistema":"ETRS89 / UTM 29N · metros","Origen del modelo":"X 729400 · Y 4301550 · Z 285 m","Alcance":"Hasta 200 m desde el lindero del proyecto; solo exterior de parcela","Planta":"Distribución ilustrativa autorizada","Altimetría":"Plano ajustado a 213 puntos XYZ de aceras, extrapolado al resto del contexto; no es un MDT levantado"}; IncluirEnMediciones: no; Criterio: {"enabled":true,"basis":"Distribución aproximada autorizada. No acredita la posición ni el número real de plazas o farolas existentes.","pending":["Posición real del mobiliario","Dimensiones y niveles definitivos"]}

# IfcLightFixture: Luminaria del entorno · ilustrativa 2
In: Parcela industrial Jinhong
Description: Entorno de coordinación: trazados derivados de las fuentes indicadas por elemento; cotas, espesores, acabados y mobiliario orientativos cuando no están documentados. No acredita propiedad, servidumbres ni cantidades de obra y no es una base de construcción.; PredefinedType: USERDEFINED; Document: Indicación del cliente · entorno de 200 m con aparcamientos y luminarias ilustrativos; Entorno de Expacio Mérida · Catastro INSPIRE, PNOA y levantamiento Berrio; Levantamiento Berrio · parcelas I-27 Vial 3 e I-18 Vial 4; IGN · ortofotografía PNOA de máxima actualidad; Group: BIM · Entorno · aparcamientos y luminarias
JH_InformacionBIM - buildingId: context; buildingName: Entorno exterior de la parcela; level: Exterior · contexto de 200 m; category: Luminaria del entorno · ilustrativa 2; ifcClass: IfcLightFixture; status: provisional; source: {"documentId":"JH-CLIENT-CONTEXT-20260909","title":"Indicación del cliente · entorno de 200 m con aparcamientos y luminarias ilustrativos","date":"2026-09-09","note":"Distribución aproximada autorizada. No acredita la posición ni el número real de plazas o farolas existentes."}; material: {"name":"Luminaria exterior · gris","status":"provisional","source":"Acabado visual aproximado; no especificación de proyecto."}; appearance: {"profileId":"ctx_light","name":"Luminaria exterior · gris","status":"criterio_visual","basis":"Acabado de contexto orientativo, sin especificación de obra."}; dimensions: {"documented":[],"assumed":[{"label":"Altura de poste","value":8,"unit":"m"},{"label":"Vuelo de brazo","value":1.4,"unit":"m"}],"geometry":[]}; classification: {"layerId":"context_furniture","layerName":"Entorno · aparcamientos y luminarias","function":"Luminaria del entorno · ilustrativa 2"}; visualLayer: {"id":"context_furniture","name":"Entorno · aparcamientos y luminarias","defaultVisible":false}; representationKind: entorno_ilustrativo; quantityEligible: no; positioning: {"Sistema":"ETRS89 / UTM 29N · metros","Origen del modelo":"X 729400 · Y 4301550 · Z 285 m","Alcance":"Hasta 200 m desde el lindero del proyecto; solo exterior de parcela","Planta":"Distribución ilustrativa autorizada","Altimetría":"Plano ajustado a 213 puntos XYZ de aceras, extrapolado al resto del contexto; no es un MDT levantado"}; issues: ["Contexto para lectura del emplazamiento; planta derivada de cartografía, cotas y detalles simplificados. No para construcción ni mediciones de obra.","Las mediciones en el entorno expresan la geometría representada y conservan la precisión de su fuente."]; conceptual: {"enabled":true,"basis":"Distribución aproximada autorizada. No acredita la posición ni el número real de plazas o farolas existentes.","pending":["Posición real del mobiliario","Dimensiones y niveles definitivos"]}; geometryMetrics: {"boundingBoxM":{"min":[-42.921915,-77.347203,-0.142619],"max":[-41.011832,-76.864969,7.967381]},"extentsM":[1.910083,0.482234,8.11],"meshSurfaceM2":5.532364,"meshVolumeM3":0.181319,"closedSolid":true,"basis":"Entorno de coordinación: trazados derivados de las fuentes indicadas por elemento; cotas, espesores, acabados y mobiliario orientativos cuando no están documentados. No acredita propiedad, servidumbres ni cantidades de obra y no es una base de construcción."}
JH_Trazabilidad - Origen: Indicación del cliente · entorno de 200 m con aparcamientos y luminarias ilustrativos; Estado: provisional; Capa BIM: Entorno · aparcamientos y luminarias; Mediciones de obra: Excluido; Identificador: CTX-LIGHT-02; Categoria: Luminaria del entorno · ilustrativa 2; ClaseIFC: IfcLightFixture; EstadoDeInformacion: provisional; DocumentoFuente: {"documentId":"JH-CLIENT-CONTEXT-20260909","title":"Indicación del cliente · entorno de 200 m con aparcamientos y luminarias ilustrativos","date":"2026-09-09","note":"Distribución aproximada autorizada. No acredita la posición ni el número real de plazas o farolas existentes."}; IncidenciasPendientes: ["Contexto para lectura del emplazamiento; planta derivada de cartografía, cotas y detalles simplificados. No para construcción ni mediciones de obra.","Las mediciones en el entorno expresan la geometría representada y conservan la precisión de su fuente."]; UsoDeLasMagnitudes: Entorno de coordinación: trazados derivados de las fuentes indicadas por elemento; cotas, espesores, acabados y mobiliario orientativos cuando no están documentados. No acredita propiedad, servidumbres ni cantidades de obra y no es una base de construcción.
JH_CriterioDePosicion - PosicionYEstado: {"Sistema":"ETRS89 / UTM 29N · metros","Origen del modelo":"X 729400 · Y 4301550 · Z 285 m","Alcance":"Hasta 200 m desde el lindero del proyecto; solo exterior de parcela","Planta":"Distribución ilustrativa autorizada","Altimetría":"Plano ajustado a 213 puntos XYZ de aceras, extrapolado al resto del contexto; no es un MDT levantado"}
JH_EvidenciaDeMaterial - name: Luminaria exterior · gris; status: provisional; source: Acabado visual aproximado; no especificación de proyecto.
JH_CapaBIM - IdentificadorCapa: context_furniture; NombreCapa: Entorno · aparcamientos y luminarias; Funcion: Luminaria del entorno · ilustrativa 2; VisibilidadInicial: no
JH_EntornoContexto - Estado: provisional; Origen: {"documentId":"JH-CLIENT-CONTEXT-20260909","title":"Indicación del cliente · entorno de 200 m con aparcamientos y luminarias ilustrativos","date":"2026-09-09","note":"Distribución aproximada autorizada. No acredita la posición ni el número real de plazas o farolas existentes."}; Posicion: {"Sistema":"ETRS89 / UTM 29N · metros","Origen del modelo":"X 729400 · Y 4301550 · Z 285 m","Alcance":"Hasta 200 m desde el lindero del proyecto; solo exterior de parcela","Planta":"Distribución ilustrativa autorizada","Altimetría":"Plano ajustado a 213 puntos XYZ de aceras, extrapolado al resto del contexto; no es un MDT levantado"}; DimensionesSupuestas: [{"label":"Altura de poste","value":8,"unit":"m"},{"label":"Vuelo de brazo","value":1.4,"unit":"m"}]; IncluirEnMediciones: no; EsquemaIlustrativo: yes; Criterio: Entorno de coordinación: trazados derivados de las fuentes indicadas por elemento; cotas, espesores, acabados y mobiliario orientativos cuando no están documentados. No acredita propiedad, servidumbres ni cantidades de obra y no es una base de construcción.
JH_EsquemaProvisional - Estado: No para construcción; Origen: {"documentId":"JH-CLIENT-CONTEXT-20260909","title":"Indicación del cliente · entorno de 200 m con aparcamientos y luminarias ilustrativos","date":"2026-09-09","note":"Distribución aproximada autorizada. No acredita la posición ni el número real de plazas o farolas existentes."}; DimensionesSupuestas: [{"label":"Altura de poste","value":8,"unit":"m"},{"label":"Vuelo de brazo","value":1.4,"unit":"m"}]; Posicion: {"Sistema":"ETRS89 / UTM 29N · metros","Origen del modelo":"X 729400 · Y 4301550 · Z 285 m","Alcance":"Hasta 200 m desde el lindero del proyecto; solo exterior de parcela","Planta":"Distribución ilustrativa autorizada","Altimetría":"Plano ajustado a 213 puntos XYZ de aceras, extrapolado al resto del contexto; no es un MDT levantado"}; IncluirEnMediciones: no; Criterio: {"enabled":true,"basis":"Distribución aproximada autorizada. No acredita la posición ni el número real de plazas o farolas existentes.","pending":["Posición real del mobiliario","Dimensiones y niveles definitivos"]}

# IfcLightFixture: Luminaria del entorno · ilustrativa 20
In: Parcela industrial Jinhong
Description: Entorno de coordinación: trazados derivados de las fuentes indicadas por elemento; cotas, espesores, acabados y mobiliario orientativos cuando no están documentados. No acredita propiedad, servidumbres ni cantidades de obra y no es una base de construcción.; PredefinedType: USERDEFINED; Document: Indicación del cliente · entorno de 200 m con aparcamientos y luminarias ilustrativos; Entorno de Expacio Mérida · Catastro INSPIRE, PNOA y levantamiento Berrio; Levantamiento Berrio · parcelas I-27 Vial 3 e I-18 Vial 4; IGN · ortofotografía PNOA de máxima actualidad; Group: BIM · Entorno · aparcamientos y luminarias
JH_InformacionBIM - buildingId: context; buildingName: Entorno exterior de la parcela; level: Exterior · contexto de 200 m; category: Luminaria del entorno · ilustrativa 20; ifcClass: IfcLightFixture; status: provisional; source: {"documentId":"JH-CLIENT-CONTEXT-20260909","title":"Indicación del cliente · entorno de 200 m con aparcamientos y luminarias ilustrativos","date":"2026-09-09","note":"Distribución aproximada autorizada. No acredita la posición ni el número real de plazas o farolas existentes."}; material: {"name":"Luminaria exterior · gris","status":"provisional","source":"Acabado visual aproximado; no especificación de proyecto."}; appearance: {"profileId":"ctx_light","name":"Luminaria exterior · gris","status":"criterio_visual","basis":"Acabado de contexto orientativo, sin especificación de obra."}; dimensions: {"documented":[],"assumed":[{"label":"Altura de poste","value":8,"unit":"m"},{"label":"Vuelo de brazo","value":1.4,"unit":"m"}],"geometry":[]}; classification: {"layerId":"context_furniture","layerName":"Entorno · aparcamientos y luminarias","function":"Luminaria del entorno · ilustrativa 20"}; visualLayer: {"id":"context_furniture","name":"Entorno · aparcamientos y luminarias","defaultVisible":false}; representationKind: entorno_ilustrativo; quantityEligible: no; positioning: {"Sistema":"ETRS89 / UTM 29N · metros","Origen del modelo":"X 729400 · Y 4301550 · Z 285 m","Alcance":"Hasta 200 m desde el lindero del proyecto; solo exterior de parcela","Planta":"Distribución ilustrativa autorizada","Altimetría":"Plano ajustado a 213 puntos XYZ de aceras, extrapolado al resto del contexto; no es un MDT levantado"}; issues: ["Contexto para lectura del emplazamiento; planta derivada de cartografía, cotas y detalles simplificados. No para construcción ni mediciones de obra.","Las mediciones en el entorno expresan la geometría representada y conservan la precisión de su fuente."]; conceptual: {"enabled":true,"basis":"Distribución aproximada autorizada. No acredita la posición ni el número real de plazas o farolas existentes.","pending":["Posición real del mobiliario","Dimensiones y niveles definitivos"]}; geometryMetrics: {"boundingBoxM":{"min":[254.505796,-12.495932,3.419037],"max":[255.211831,-10.744027,11.529037]},"extentsM":[0.706035,1.751905,8.11],"meshSurfaceM2":5.532363,"meshVolumeM3":0.181319,"closedSolid":true,"basis":"Entorno de coordinación: trazados derivados de las fuentes indicadas por elemento; cotas, espesores, acabados y mobiliario orientativos cuando no están documentados. No acredita propiedad, servidumbres ni cantidades de obra y no es una base de construcción."}
JH_Trazabilidad - Origen: Indicación del cliente · entorno de 200 m con aparcamientos y luminarias ilustrativos; Estado: provisional; Capa BIM: Entorno · aparcamientos y luminarias; Mediciones de obra: Excluido; Identificador: CTX-LIGHT-20; Categoria: Luminaria del entorno · ilustrativa 20; ClaseIFC: IfcLightFixture; EstadoDeInformacion: provisional; DocumentoFuente: {"documentId":"JH-CLIENT-CONTEXT-20260909","title":"Indicación del cliente · entorno de 200 m con aparcamientos y luminarias ilustrativos","date":"2026-09-09","note":"Distribución aproximada autorizada. No acredita la posición ni el número real de plazas o farolas existentes."}; IncidenciasPendientes: ["Contexto para lectura del emplazamiento; planta derivada de cartografía, cotas y detalles simplificados. No para construcción ni mediciones de obra.","Las mediciones en el entorno expresan la geometría representada y conservan la precisión de su fuente."]; UsoDeLasMagnitudes: Entorno de coordinación: trazados derivados de las fuentes indicadas por elemento; cotas, espesores, acabados y mobiliario orientativos cuando no están documentados. No acredita propiedad, servidumbres ni cantidades de obra y no es una base de construcción.
JH_CriterioDePosicion - PosicionYEstado: {"Sistema":"ETRS89 / UTM 29N · metros","Origen del modelo":"X 729400 · Y 4301550 · Z 285 m","Alcance":"Hasta 200 m desde el lindero del proyecto; solo exterior de parcela","Planta":"Distribución ilustrativa autorizada","Altimetría":"Plano ajustado a 213 puntos XYZ de aceras, extrapolado al resto del contexto; no es un MDT levantado"}
JH_EvidenciaDeMaterial - name: Luminaria exterior · gris; status: provisional; source: Acabado visual aproximado; no especificación de proyecto.
JH_CapaBIM - IdentificadorCapa: context_furniture; NombreCapa: Entorno · aparcamientos y luminarias; Funcion: Luminaria del entorno · ilustrativa 20; VisibilidadInicial: no
JH_EntornoContexto - Estado: provisional; Origen: {"documentId":"JH-CLIENT-CONTEXT-20260909","title":"Indicación del cliente · entorno de 200 m con aparcamientos y luminarias ilustrativos","date":"2026-09-09","note":"Distribución aproximada autorizada. No acredita la posición ni el número real de plazas o farolas existentes."}; Posicion: {"Sistema":"ETRS89 / UTM 29N · metros","Origen del modelo":"X 729400 · Y 4301550 · Z 285 m","Alcance":"Hasta 200 m desde el lindero del proyecto; solo exterior de parcela","Planta":"Distribución ilustrativa autorizada","Altimetría":"Plano ajustado a 213 puntos XYZ de aceras, extrapolado al resto del contexto; no es un MDT levantado"}; DimensionesSupuestas: [{"label":"Altura de poste","value":8,"unit":"m"},{"label":"Vuelo de brazo","value":1.4,"unit":"m"}]; IncluirEnMediciones: no; EsquemaIlustrativo: yes; Criterio: Entorno de coordinación: trazados derivados de las fuentes indicadas por elemento; cotas, espesores, acabados y mobiliario orientativos cuando no están documentados. No acredita propiedad, servidumbres ni cantidades de obra y no es una base de construcción.
JH_EsquemaProvisional - Estado: No para construcción; Origen: {"documentId":"JH-CLIENT-CONTEXT-20260909","title":"Indicación del cliente · entorno de 200 m con aparcamientos y luminarias ilustrativos","date":"2026-09-09","note":"Distribución aproximada autorizada. No acredita la posición ni el número real de plazas o farolas existentes."}; DimensionesSupuestas: [{"label":"Altura de poste","value":8,"unit":"m"},{"label":"Vuelo de brazo","value":1.4,"unit":"m"}]; Posicion: {"Sistema":"ETRS89 / UTM 29N · metros","Origen del modelo":"X 729400 · Y 4301550 · Z 285 m","Alcance":"Hasta 200 m desde el lindero del proyecto; solo exterior de parcela","Planta":"Distribución ilustrativa autorizada","Altimetría":"Plano ajustado a 213 puntos XYZ de aceras, extrapolado al resto del contexto; no es un MDT levantado"}; IncluirEnMediciones: no; Criterio: {"enabled":true,"basis":"Distribución aproximada autorizada. No acredita la posición ni el número real de plazas o farolas existentes.","pending":["Posición real del mobiliario","Dimensiones y niveles definitivos"]}

# IfcLightFixture: Luminaria del entorno · ilustrativa 21
In: Parcela industrial Jinhong
Description: Entorno de coordinación: trazados derivados de las fuentes indicadas por elemento; cotas, espesores, acabados y mobiliario orientativos cuando no están documentados. No acredita propiedad, servidumbres ni cantidades de obra y no es una base de construcción.; PredefinedType: USERDEFINED; Document: Indicación del cliente · entorno de 200 m con aparcamientos y luminarias ilustrativos; Entorno de Expacio Mérida · Catastro INSPIRE, PNOA y levantamiento Berrio; Levantamiento Berrio · parcelas I-27 Vial 3 e I-18 Vial 4; IGN · ortofotografía PNOA de máxima actualidad; Group: BIM · Entorno · aparcamientos y luminarias
JH_InformacionBIM - buildingId: context; buildingName: Entorno exterior de la parcela; level: Exterior · contexto de 200 m; category: Luminaria del entorno · ilustrativa 21; ifcClass: IfcLightFixture; status: provisional; source: {"documentId":"JH-CLIENT-CONTEXT-20260909","title":"Indicación del cliente · entorno de 200 m con aparcamientos y luminarias ilustrativos","date":"2026-09-09","note":"Distribución aproximada autorizada. No acredita la posición ni el número real de plazas o farolas existentes."}; material: {"name":"Luminaria exterior · gris","status":"provisional","source":"Acabado visual aproximado; no especificación de proyecto."}; appearance: {"profileId":"ctx_light","name":"Luminaria exterior · gris","status":"criterio_visual","basis":"Acabado de contexto orientativo, sin especificación de obra."}; dimensions: {"documented":[],"assumed":[{"label":"Altura de poste","value":8,"unit":"m"},{"label":"Vuelo de brazo","value":1.4,"unit":"m"}],"geometry":[]}; classification: {"layerId":"context_furniture","layerName":"Entorno · aparcamientos y luminarias","function":"Luminaria del entorno · ilustrativa 21"}; visualLayer: {"id":"context_furniture","name":"Entorno · aparcamientos y luminarias","defaultVisible":false}; representationKind: entorno_ilustrativo; quantityEligible: no; positioning: {"Sistema":"ETRS89 / UTM 29N · metros","Origen del modelo":"X 729400 · Y 4301550 · Z 285 m","Alcance":"Hasta 200 m desde el lindero del proyecto; solo exterior de parcela","Planta":"Distribución ilustrativa autorizada","Altimetría":"Plano ajustado a 213 puntos XYZ de aceras, extrapolado al resto del contexto; no es un MDT levantado"}; issues: ["Contexto para lectura del emplazamiento; planta derivada de cartografía, cotas y detalles simplificados. No para construcción ni mediciones de obra.","Las mediciones en el entorno expresan la geometría representada y conservan la precisión de su fuente."]; conceptual: {"enabled":true,"basis":"Distribución aproximada autorizada. No acredita la posición ni el número real de plazas o farolas existentes.","pending":["Posición real del mobiliario","Dimensiones y niveles definitivos"]}; geometryMetrics: {"boundingBoxM":{"min":[281.75487,-49.737844,3.623154],"max":[282.460905,-47.985939,11.733154]},"extentsM":[0.706035,1.751905,8.11],"meshSurfaceM2":5.532363,"meshVolumeM3":0.181319,"closedSolid":true,"basis":"Entorno de coordinación: trazados derivados de las fuentes indicadas por elemento; cotas, espesores, acabados y mobiliario orientativos cuando no están documentados. No acredita propiedad, servidumbres ni cantidades de obra y no es una base de construcción."}
JH_Trazabilidad - Origen: Indicación del cliente · entorno de 200 m con aparcamientos y luminarias ilustrativos; Estado: provisional; Capa BIM: Entorno · aparcamientos y luminarias; Mediciones de obra: Excluido; Identificador: CTX-LIGHT-21; Categoria: Luminaria del entorno · ilustrativa 21; ClaseIFC: IfcLightFixture; EstadoDeInformacion: provisional; DocumentoFuente: {"documentId":"JH-CLIENT-CONTEXT-20260909","title":"Indicación del cliente · entorno de 200 m con aparcamientos y luminarias ilustrativos","date":"2026-09-09","note":"Distribución aproximada autorizada. No acredita la posición ni el número real de plazas o farolas existentes."}; IncidenciasPendientes: ["Contexto para lectura del emplazamiento; planta derivada de cartografía, cotas y detalles simplificados. No para construcción ni mediciones de obra.","Las mediciones en el entorno expresan la geometría representada y conservan la precisión de su fuente."]; UsoDeLasMagnitudes: Entorno de coordinación: trazados derivados de las fuentes indicadas por elemento; cotas, espesores, acabados y mobiliario orientativos cuando no están documentados. No acredita propiedad, servidumbres ni cantidades de obra y no es una base de construcción.
JH_CriterioDePosicion - PosicionYEstado: {"Sistema":"ETRS89 / UTM 29N · metros","Origen del modelo":"X 729400 · Y 4301550 · Z 285 m","Alcance":"Hasta 200 m desde el lindero del proyecto; solo exterior de parcela","Planta":"Distribución ilustrativa autorizada","Altimetría":"Plano ajustado a 213 puntos XYZ de aceras, extrapolado al resto del contexto; no es un MDT levantado"}
JH_EvidenciaDeMaterial - name: Luminaria exterior · gris; status: provisional; source: Acabado visual aproximado; no especificación de proyecto.
JH_CapaBIM - IdentificadorCapa: context_furniture; NombreCapa: Entorno · aparcamientos y luminarias; Funcion: Luminaria del entorno · ilustrativa 21; VisibilidadInicial: no
JH_EntornoContexto - Estado: provisional; Origen: {"documentId":"JH-CLIENT-CONTEXT-20260909","title":"Indicación del cliente · entorno de 200 m con aparcamientos y luminarias ilustrativos","date":"2026-09-09","note":"Distribución aproximada autorizada. No acredita la posición ni el número real de plazas o farolas existentes."}; Posicion: {"Sistema":"ETRS89 / UTM 29N · metros","Origen del modelo":"X 729400 · Y 4301550 · Z 285 m","Alcance":"Hasta 200 m desde el lindero del proyecto; solo exterior de parcela","Planta":"Distribución ilustrativa autorizada","Altimetría":"Plano ajustado a 213 puntos XYZ de aceras, extrapolado al resto del contexto; no es un MDT levantado"}; DimensionesSupuestas: [{"label":"Altura de poste","value":8,"unit":"m"},{"label":"Vuelo de brazo","value":1.4,"unit":"m"}]; IncluirEnMediciones: no; EsquemaIlustrativo: yes; Criterio: Entorno de coordinación: trazados derivados de las fuentes indicadas por elemento; cotas, espesores, acabados y mobiliario orientativos cuando no están documentados. No acredita propiedad, servidumbres ni cantidades de obra y no es una base de construcción.
JH_EsquemaProvisional - Estado: No para construcción; Origen: {"documentId":"JH-CLIENT-CONTEXT-20260909","title":"Indicación del cliente · entorno de 200 m con aparcamientos y luminarias ilustrativos","date":"2026-09-09","note":"Distribución aproximada autorizada. No acredita la posición ni el número real de plazas o farolas existentes."}; DimensionesSupuestas: [{"label":"Altura de poste","value":8,"unit":"m"},{"label":"Vuelo de brazo","value":1.4,"unit":"m"}]; Posicion: {"Sistema":"ETRS89 / UTM 29N · metros","Origen del modelo":"X 729400 · Y 4301550 · Z 285 m","Alcance":"Hasta 200 m desde el lindero del proyecto; solo exterior de parcela","Planta":"Distribución ilustrativa autorizada","Altimetría":"Plano ajustado a 213 puntos XYZ de aceras, extrapolado al resto del contexto; no es un MDT levantado"}; IncluirEnMediciones: no; Criterio: {"enabled":true,"basis":"Distribución aproximada autorizada. No acredita la posición ni el número real de plazas o farolas existentes.","pending":["Posición real del mobiliario","Dimensiones y niveles definitivos"]}

# IfcLightFixture: Luminaria del entorno · ilustrativa 22
In: Parcela industrial Jinhong
Description: Entorno de coordinación: trazados derivados de las fuentes indicadas por elemento; cotas, espesores, acabados y mobiliario orientativos cuando no están documentados. No acredita propiedad, servidumbres ni cantidades de obra y no es una base de construcción.; PredefinedType: USERDEFINED; Document: Indicación del cliente · entorno de 200 m con aparcamientos y luminarias ilustrativos; Entorno de Expacio Mérida · Catastro INSPIRE, PNOA y levantamiento Berrio; Levantamiento Berrio · parcelas I-27 Vial 3 e I-18 Vial 4; IGN · ortofotografía PNOA de máxima actualidad; Group: BIM · Entorno · aparcamientos y luminarias
JH_InformacionBIM - buildingId: context; buildingName: Entorno exterior de la parcela; level: Exterior · contexto de 200 m; category: Luminaria del entorno · ilustrativa 22; ifcClass: IfcLightFixture; status: provisional; source: {"documentId":"JH-CLIENT-CONTEXT-20260909","title":"Indicación del cliente · entorno de 200 m con aparcamientos y luminarias ilustrativos","date":"2026-09-09","note":"Distribución aproximada autorizada. No acredita la posición ni el número real de plazas o farolas existentes."}; material: {"name":"Luminaria exterior · gris","status":"provisional","source":"Acabado visual aproximado; no especificación de proyecto."}; appearance: {"profileId":"ctx_light","name":"Luminaria exterior · gris","status":"criterio_visual","basis":"Acabado de contexto orientativo, sin especificación de obra."}; dimensions: {"documented":[],"assumed":[{"label":"Altura de poste","value":8,"unit":"m"},{"label":"Vuelo de brazo","value":1.4,"unit":"m"}],"geometry":[]}; classification: {"layerId":"context_furniture","layerName":"Entorno · aparcamientos y luminarias","function":"Luminaria del entorno · ilustrativa 22"}; visualLayer: {"id":"context_furniture","name":"Entorno · aparcamientos y luminarias","defaultVisible":false}; representationKind: entorno_ilustrativo; quantityEligible: no; positioning: {"Sistema":"ETRS89 / UTM 29N · metros","Origen del modelo":"X 729400 · Y 4301550 · Z 285 m","Alcance":"Hasta 200 m desde el lindero del proyecto; solo exterior de parcela","Planta":"Distribución ilustrativa autorizada","Altimetría":"Plano ajustado a 213 puntos XYZ de aceras, extrapolado al resto del contexto; no es un MDT levantado"}; issues: ["Contexto para lectura del emplazamiento; planta derivada de cartografía, cotas y detalles simplificados. No para construcción ni mediciones de obra.","Las mediciones en el entorno expresan la geometría representada y conservan la precisión de su fuente."]; conceptual: {"enabled":true,"basis":"Distribución aproximada autorizada. No acredita la posición ni el número real de plazas o farolas existentes.","pending":["Posición real del mobiliario","Dimensiones y niveles definitivos"]}; geometryMetrics: {"boundingBoxM":{"min":[286.206483,-16.862446,3.767883],"max":[286.912518,-15.110541,11.877883]},"extentsM":[0.706035,1.751905,8.11],"meshSurfaceM2":5.532365,"meshVolumeM3":0.181319,"closedSolid":true,"basis":"Entorno de coordinación: trazados derivados de las fuentes indicadas por elemento; cotas, espesores, acabados y mobiliario orientativos cuando no están documentados. No acredita propiedad, servidumbres ni cantidades de obra y no es una base de construcción."}
JH_Trazabilidad - Origen: Indicación del cliente · entorno de 200 m con aparcamientos y luminarias ilustrativos; Estado: provisional; Capa BIM: Entorno · aparcamientos y luminarias; Mediciones de obra: Excluido; Identificador: CTX-LIGHT-22; Categoria: Luminaria del entorno · ilustrativa 22; ClaseIFC: IfcLightFixture; EstadoDeInformacion: provisional; DocumentoFuente: {"documentId":"JH-CLIENT-CONTEXT-20260909","title":"Indicación del cliente · entorno de 200 m con aparcamientos y luminarias ilustrativos","date":"2026-09-09","note":"Distribución aproximada autorizada. No acredita la posición ni el número real de plazas o farolas existentes."}; IncidenciasPendientes: ["Contexto para lectura del emplazamiento; planta derivada de cartografía, cotas y detalles simplificados. No para construcción ni mediciones de obra.","Las mediciones en el entorno expresan la geometría representada y conservan la precisión de su fuente."]; UsoDeLasMagnitudes: Entorno de coordinación: trazados derivados de las fuentes indicadas por elemento; cotas, espesores, acabados y mobiliario orientativos cuando no están documentados. No acredita propiedad, servidumbres ni cantidades de obra y no es una base de construcción.
JH_CriterioDePosicion - PosicionYEstado: {"Sistema":"ETRS89 / UTM 29N · metros","Origen del modelo":"X 729400 · Y 4301550 · Z 285 m","Alcance":"Hasta 200 m desde el lindero del proyecto; solo exterior de parcela","Planta":"Distribución ilustrativa autorizada","Altimetría":"Plano ajustado a 213 puntos XYZ de aceras, extrapolado al resto del contexto; no es un MDT levantado"}
JH_EvidenciaDeMaterial - name: Luminaria exterior · gris; status: provisional; source: Acabado visual aproximado; no especificación de proyecto.
JH_CapaBIM - IdentificadorCapa: context_furniture; NombreCapa: Entorno · aparcamientos y luminarias; Funcion: Luminaria del entorno · ilustrativa 22; VisibilidadInicial: no
JH_EntornoContexto - Estado: provisional; Origen: {"documentId":"JH-CLIENT-CONTEXT-20260909","title":"Indicación del cliente · entorno de 200 m con aparcamientos y luminarias ilustrativos","date":"2026-09-09","note":"Distribución aproximada autorizada. No acredita la posición ni el número real de plazas o farolas existentes."}; Posicion: {"Sistema":"ETRS89 / UTM 29N · metros","Origen del modelo":"X 729400 · Y 4301550 · Z 285 m","Alcance":"Hasta 200 m desde el lindero del proyecto; solo exterior de parcela","Planta":"Distribución ilustrativa autorizada","Altimetría":"Plano ajustado a 213 puntos XYZ de aceras, extrapolado al resto del contexto; no es un MDT levantado"}; DimensionesSupuestas: [{"label":"Altura de poste","value":8,"unit":"m"},{"label":"Vuelo de brazo","value":1.4,"unit":"m"}]; IncluirEnMediciones: no; EsquemaIlustrativo: yes; Criterio: Entorno de coordinación: trazados derivados de las fuentes indicadas por elemento; cotas, espesores, acabados y mobiliario orientativos cuando no están documentados. No acredita propiedad, servidumbres ni cantidades de obra y no es una base de construcción.
JH_EsquemaProvisional - Estado: No para construcción; Origen: {"documentId":"JH-CLIENT-CONTEXT-20260909","title":"Indicación del cliente · entorno de 200 m con aparcamientos y luminarias ilustrativos","date":"2026-09-09","note":"Distribución aproximada autorizada. No acredita la posición ni el número real de plazas o farolas existentes."}; DimensionesSupuestas: [{"label":"Altura de poste","value":8,"unit":"m"},{"label":"Vuelo de brazo","value":1.4,"unit":"m"}]; Posicion: {"Sistema":"ETRS89 / UTM 29N · metros","Origen del modelo":"X 729400 · Y 4301550 · Z 285 m","Alcance":"Hasta 200 m desde el lindero del proyecto; solo exterior de parcela","Planta":"Distribución ilustrativa autorizada","Altimetría":"Plano ajustado a 213 puntos XYZ de aceras, extrapolado al resto del contexto; no es un MDT levantado"}; IncluirEnMediciones: no; Criterio: {"enabled":true,"basis":"Distribución aproximada autorizada. No acredita la posición ni el número real de plazas o farolas existentes.","pending":["Posición real del mobiliario","Dimensiones y niveles definitivos"]}

# IfcLightFixture: Luminaria del entorno · ilustrativa 23
In: Parcela industrial Jinhong
Description: Entorno de coordinación: trazados derivados de las fuentes indicadas por elemento; cotas, espesores, acabados y mobiliario orientativos cuando no están documentados. No acredita propiedad, servidumbres ni cantidades de obra y no es una base de construcción.; PredefinedType: USERDEFINED; Document: Indicación del cliente · entorno de 200 m con aparcamientos y luminarias ilustrativos; Entorno de Expacio Mérida · Catastro INSPIRE, PNOA y levantamiento Berrio; Levantamiento Berrio · parcelas I-27 Vial 3 e I-18 Vial 4; IGN · ortofotografía PNOA de máxima actualidad; Group: BIM · Entorno · aparcamientos y luminarias
JH_InformacionBIM - buildingId: context; buildingName: Entorno exterior de la parcela; level: Exterior · contexto de 200 m; category: Luminaria del entorno · ilustrativa 23; ifcClass: IfcLightFixture; status: provisional; source: {"documentId":"JH-CLIENT-CONTEXT-20260909","title":"Indicación del cliente · entorno de 200 m con aparcamientos y luminarias ilustrativos","date":"2026-09-09","note":"Distribución aproximada autorizada. No acredita la posición ni el número real de plazas o farolas existentes."}; material: {"name":"Luminaria exterior · gris","status":"provisional","source":"Acabado visual aproximado; no especificación de proyecto."}; appearance: {"profileId":"ctx_light","name":"Luminaria exterior · gris","status":"criterio_visual","basis":"Acabado de contexto orientativo, sin especificación de obra."}; dimensions: {"documented":[],"assumed":[{"label":"Altura de poste","value":8,"unit":"m"},{"label":"Vuelo de brazo","value":1.4,"unit":"m"}],"geometry":[]}; classification: {"layerId":"context_furniture","layerName":"Entorno · aparcamientos y luminarias","function":"Luminaria del entorno · ilustrativa 23"}; visualLayer: {"id":"context_furniture","name":"Entorno · aparcamientos y luminarias","defaultVisible":false}; representationKind: entorno_ilustrativo; quantityEligible: no; positioning: {"Sistema":"ETRS89 / UTM 29N · metros","Origen del modelo":"X 729400 · Y 4301550 · Z 285 m","Alcance":"Hasta 200 m desde el lindero del proyecto; solo exterior de parcela","Planta":"Distribución ilustrativa autorizada","Altimetría":"Plano ajustado a 213 puntos XYZ de aceras, extrapolado al resto del contexto; no es un MDT levantado"}; issues: ["Contexto para lectura del emplazamiento; planta derivada de cartografía, cotas y detalles simplificados. No para construcción ni mediciones de obra.","Las mediciones en el entorno expresan la geometría representada y conservan la precisión de su fuente."]; conceptual: {"enabled":true,"basis":"Distribución aproximada autorizada. No acredita la posición ni el número real de plazas o farolas existentes.","pending":["Posición real del mobiliario","Dimensiones y niveles definitivos"]}; geometryMetrics: {"boundingBoxM":{"min":[317.497809,-24.200899,4.104143],"max":[318.203844,-22.448994,12.214143]},"extentsM":[0.706035,1.751905,8.11],"meshSurfaceM2":5.532367,"meshVolumeM3":0.181319,"closedSolid":true,"basis":"Entorno de coordinación: trazados derivados de las fuentes indicadas por elemento; cotas, espesores, acabados y mobiliario orientativos cuando no están documentados. No acredita propiedad, servidumbres ni cantidades de obra y no es una base de construcción."}
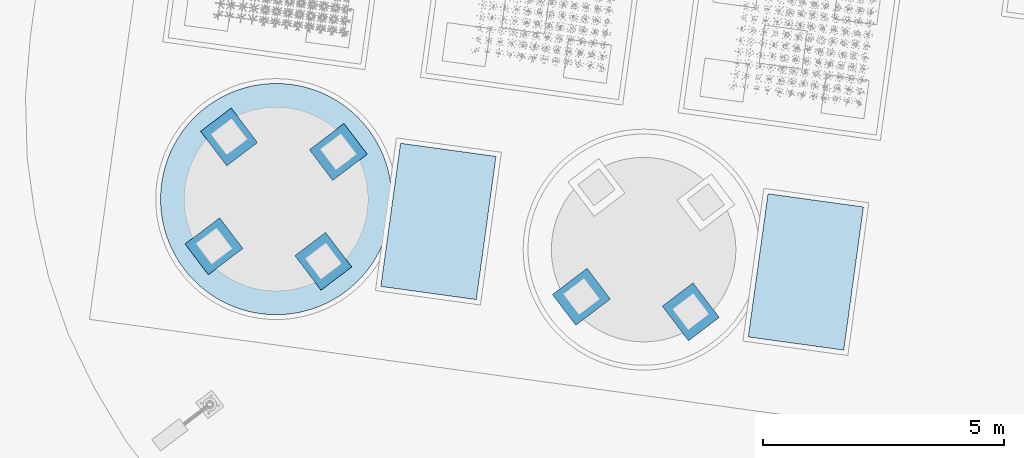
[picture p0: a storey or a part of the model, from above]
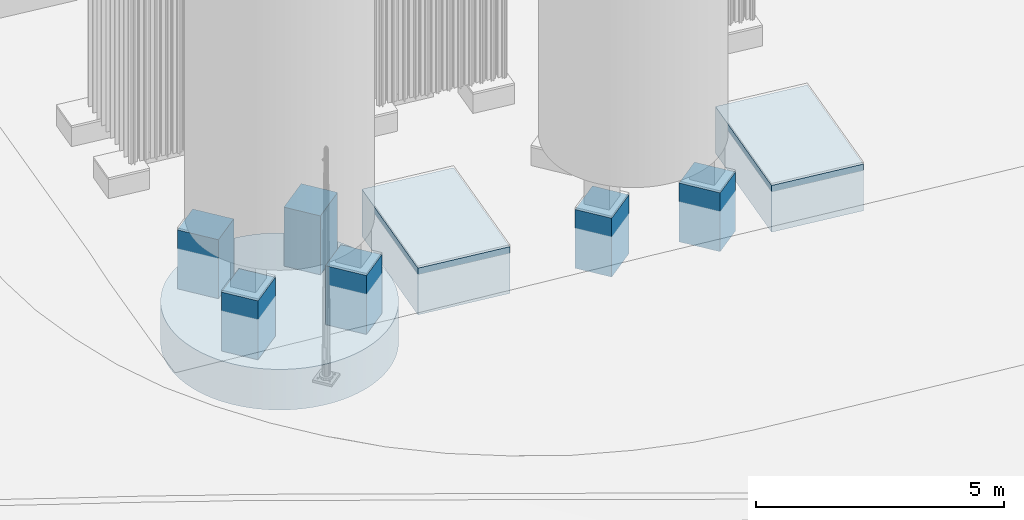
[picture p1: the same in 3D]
Properties of the parts of a building model (IFC4), part 92 of 134

# IfcLightFixture: Luminaria del entorno · ilustrativa 23
JH_Trazabilidad - Origen: Indicación del cliente · entorno de 200 m con aparcamientos y luminarias ilustrativos; Estado: provisional; Capa BIM: Entorno · aparcamientos y luminarias; Mediciones de obra: Excluido; Identificador: CTX-LIGHT-23; Categoria: Luminaria del entorno · ilustrativa 23; ClaseIFC: IfcLightFixture; EstadoDeInformacion: provisional; DocumentoFuente: {"documentId":"JH-CLIENT-CONTEXT-20260909","title":"Indicación del cliente · entorno de 200 m con aparcamientos y luminarias ilustrativos","date":"2026-09-09","note":"Distribución aproximada autorizada. No acredita la posición ni el número real de plazas o farolas existentes."}; IncidenciasPendientes: ["Contexto para lectura del emplazamiento; planta derivada de cartografía, cotas y detalles simplificados. No para construcción ni mediciones de obra.","Las mediciones en el entorno expresan la geometría representada y conservan la precisión de su fuente."]; UsoDeLasMagnitudes: Entorno de coordinación: trazados derivados de las fuentes indicadas por elemento; cotas, espesores, acabados y mobiliario orientativos cuando no están documentados. No acredita propiedad, servidumbres ni cantidades de obra y no es una base de construcción.
JH_CriterioDePosicion - PosicionYEstado: {"Sistema":"ETRS89 / UTM 29N · metros","Origen del modelo":"X 729400 · Y 4301550 · Z 285 m","Alcance":"Hasta 200 m desde el lindero del proyecto; solo exterior de parcela","Planta":"Distribución ilustrativa autorizada","Altimetría":"Plano ajustado a 213 puntos XYZ de aceras, extrapolado al resto del contexto; no es un MDT levantado"}
JH_EvidenciaDeMaterial - name: Luminaria exterior · gris; status: provisional; source: Acabado visual aproximado; no especificación de proyecto.
JH_CapaBIM - IdentificadorCapa: context_furniture; NombreCapa: Entorno · aparcamientos y luminarias; Funcion: Luminaria del entorno · ilustrativa 23; VisibilidadInicial: no
JH_EntornoContexto - Estado: provisional; Origen: {"documentId":"JH-CLIENT-CONTEXT-20260909","title":"Indicación del cliente · entorno de 200 m con aparcamientos y luminarias ilustrativos","date":"2026-09-09","note":"Distribución aproximada autorizada. No acredita la posición ni el número real de plazas o farolas existentes."}; Posicion: {"Sistema":"ETRS89 / UTM 29N · metros","Origen del modelo":"X 729400 · Y 4301550 · Z 285 m","Alcance":"Hasta 200 m desde el lindero del proyecto; solo exterior de parcela","Planta":"Distribución ilustrativa autorizada","Altimetría":"Plano ajustado a 213 puntos XYZ de aceras, extrapolado al resto del contexto; no es un MDT levantado"}; DimensionesSupuestas: [{"label":"Altura de poste","value":8,"unit":"m"},{"label":"Vuelo de brazo","value":1.4,"unit":"m"}]; IncluirEnMediciones: no; EsquemaIlustrativo: yes; Criterio: Entorno de coordinación: trazados derivados de las fuentes indicadas por elemento; cotas, espesores, acabados y mobiliario orientativos cuando no están documentados. No acredita propiedad, servidumbres ni cantidades de obra y no es una base de construcción.
JH_EsquemaProvisional - Estado: No para construcción; Origen: {"documentId":"JH-CLIENT-CONTEXT-20260909","title":"Indicación del cliente · entorno de 200 m con aparcamientos y luminarias ilustrativos","date":"2026-09-09","note":"Distribución aproximada autorizada. No acredita la posición ni el número real de plazas o farolas existentes."}; DimensionesSupuestas: [{"label":"Altura de poste","value":8,"unit":"m"},{"label":"Vuelo de brazo","value":1.4,"unit":"m"}]; Posicion: {"Sistema":"ETRS89 / UTM 29N · metros","Origen del modelo":"X 729400 · Y 4301550 · Z 285 m","Alcance":"Hasta 200 m desde el lindero del proyecto; solo exterior de parcela","Planta":"Distribución ilustrativa autorizada","Altimetría":"Plano ajustado a 213 puntos XYZ de aceras, extrapolado al resto del contexto; no es un MDT levantado"}; IncluirEnMediciones: no; Criterio: {"enabled":true,"basis":"Distribución aproximada autorizada. No acredita la posición ni el número real de plazas o farolas existentes.","pending":["Posición real del mobiliario","Dimensiones y niveles definitivos"]}

# IfcLightFixture: Luminaria del entorno · ilustrativa 24
In: Parcela industrial Jinhong
Description: Entorno de coordinación: trazados derivados de las fuentes indicadas por elemento; cotas, espesores, acabados y mobiliario orientativos cuando no están documentados. No acredita propiedad, servidumbres ni cantidades de obra y no es una base de construcción.; PredefinedType: USERDEFINED; Document: Indicación del cliente · entorno de 200 m con aparcamientos y luminarias ilustrativos; Entorno de Expacio Mérida · Catastro INSPIRE, PNOA y levantamiento Berrio; Levantamiento Berrio · parcelas I-27 Vial 3 e I-18 Vial 4; IGN · ortofotografía PNOA de máxima actualidad; Group: BIM · Entorno · aparcamientos y luminarias
JH_InformacionBIM - buildingId: context; buildingName: Entorno exterior de la parcela; level: Exterior · contexto de 200 m; category: Luminaria del entorno · ilustrativa 24; ifcClass: IfcLightFixture; status: provisional; source: {"documentId":"JH-CLIENT-CONTEXT-20260909","title":"Indicación del cliente · entorno de 200 m con aparcamientos y luminarias ilustrativos","date":"2026-09-09","note":"Distribución aproximada autorizada. No acredita la posición ni el número real de plazas o farolas existentes."}; material: {"name":"Luminaria exterior · gris","status":"provisional","source":"Acabado visual aproximado; no especificación de proyecto."}; appearance: {"profileId":"ctx_light","name":"Luminaria exterior · gris","status":"criterio_visual","basis":"Acabado de contexto orientativo, sin especificación de obra."}; dimensions: {"documented":[],"assumed":[{"label":"Altura de poste","value":8,"unit":"m"},{"label":"Vuelo de brazo","value":1.4,"unit":"m"}],"geometry":[]}; classification: {"layerId":"context_furniture","layerName":"Entorno · aparcamientos y luminarias","function":"Luminaria del entorno · ilustrativa 24"}; visualLayer: {"id":"context_furniture","name":"Entorno · aparcamientos y luminarias","defaultVisible":false}; representationKind: entorno_ilustrativo; quantityEligible: no; positioning: {"Sistema":"ETRS89 / UTM 29N · metros","Origen del modelo":"X 729400 · Y 4301550 · Z 285 m","Alcance":"Hasta 200 m desde el lindero del proyecto; solo exterior de parcela","Planta":"Distribución ilustrativa autorizada","Altimetría":"Plano ajustado a 213 puntos XYZ de aceras, extrapolado al resto del contexto; no es un MDT levantado"}; issues: ["Contexto para lectura del emplazamiento; planta derivada de cartografía, cotas y detalles simplificados. No para construcción ni mediciones de obra.","Las mediciones en el entorno expresan la geometría representada y conservan la precisión de su fuente."]; conceptual: {"enabled":true,"basis":"Distribución aproximada autorizada. No acredita la posición ni el número real de plazas o farolas existentes.","pending":["Posición real del mobiliario","Dimensiones y niveles definitivos"]}; geometryMetrics: {"boundingBoxM":{"min":[-114.94074,251.816158,-0.083402],"max":[-114.231502,253.567618,8.026598]},"extentsM":[0.709238,1.75146,8.11],"meshSurfaceM2":5.532363,"meshVolumeM3":0.181319,"closedSolid":true,"basis":"Entorno de coordinación: trazados derivados de las fuentes indicadas por elemento; cotas, espesores, acabados y mobiliario orientativos cuando no están documentados. No acredita propiedad, servidumbres ni cantidades de obra y no es una base de construcción."}
JH_Trazabilidad - Origen: Indicación del cliente · entorno de 200 m con aparcamientos y luminarias ilustrativos; Estado: provisional; Capa BIM: Entorno · aparcamientos y luminarias; Mediciones de obra: Excluido; Identificador: CTX-LIGHT-24; Categoria: Luminaria del entorno · ilustrativa 24; ClaseIFC: IfcLightFixture; EstadoDeInformacion: provisional; DocumentoFuente: {"documentId":"JH-CLIENT-CONTEXT-20260909","title":"Indicación del cliente · entorno de 200 m con aparcamientos y luminarias ilustrativos","date":"2026-09-09","note":"Distribución aproximada autorizada. No acredita la posición ni el número real de plazas o farolas existentes."}; IncidenciasPendientes: ["Contexto para lectura del emplazamiento; planta derivada de cartografía, cotas y detalles simplificados. No para construcción ni mediciones de obra.","Las mediciones en el entorno expresan la geometría representada y conservan la precisión de su fuente."]; UsoDeLasMagnitudes: Entorno de coordinación: trazados derivados de las fuentes indicadas por elemento; cotas, espesores, acabados y mobiliario orientativos cuando no están documentados. No acredita propiedad, servidumbres ni cantidades de obra y no es una base de construcción.
JH_CriterioDePosicion - PosicionYEstado: {"Sistema":"ETRS89 / UTM 29N · metros","Origen del modelo":"X 729400 · Y 4301550 · Z 285 m","Alcance":"Hasta 200 m desde el lindero del proyecto; solo exterior de parcela","Planta":"Distribución ilustrativa autorizada","Altimetría":"Plano ajustado a 213 puntos XYZ de aceras, extrapolado al resto del contexto; no es un MDT levantado"}
JH_EvidenciaDeMaterial - name: Luminaria exterior · gris; status: provisional; source: Acabado visual aproximado; no especificación de proyecto.
JH_CapaBIM - IdentificadorCapa: context_furniture; NombreCapa: Entorno · aparcamientos y luminarias; Funcion: Luminaria del entorno · ilustrativa 24; VisibilidadInicial: no
JH_EntornoContexto - Estado: provisional; Origen: {"documentId":"JH-CLIENT-CONTEXT-20260909","title":"Indicación del cliente · entorno de 200 m con aparcamientos y luminarias ilustrativos","date":"2026-09-09","note":"Distribución aproximada autorizada. No acredita la posición ni el número real de plazas o farolas existentes."}; Posicion: {"Sistema":"ETRS89 / UTM 29N · metros","Origen del modelo":"X 729400 · Y 4301550 · Z 285 m","Alcance":"Hasta 200 m desde el lindero del proyecto; solo exterior de parcela","Planta":"Distribución ilustrativa autorizada","Altimetría":"Plano ajustado a 213 puntos XYZ de aceras, extrapolado al resto del contexto; no es un MDT levantado"}; DimensionesSupuestas: [{"label":"Altura de poste","value":8,"unit":"m"},{"label":"Vuelo de brazo","value":1.4,"unit":"m"}]; IncluirEnMediciones: no; EsquemaIlustrativo: yes; Criterio: Entorno de coordinación: trazados derivados de las fuentes indicadas por elemento; cotas, espesores, acabados y mobiliario orientativos cuando no están documentados. No acredita propiedad, servidumbres ni cantidades de obra y no es una base de construcción.
JH_EsquemaProvisional - Estado: No para construcción; Origen: {"documentId":"JH-CLIENT-CONTEXT-20260909","title":"Indicación del cliente · entorno de 200 m con aparcamientos y luminarias ilustrativos","date":"2026-09-09","note":"Distribución aproximada autorizada. No acredita la posición ni el número real de plazas o farolas existentes."}; DimensionesSupuestas: [{"label":"Altura de poste","value":8,"unit":"m"},{"label":"Vuelo de brazo","value":1.4,"unit":"m"}]; Posicion: {"Sistema":"ETRS89 / UTM 29N · metros","Origen del modelo":"X 729400 · Y 4301550 · Z 285 m","Alcance":"Hasta 200 m desde el lindero del proyecto; solo exterior de parcela","Planta":"Distribución ilustrativa autorizada","Altimetría":"Plano ajustado a 213 puntos XYZ de aceras, extrapolado al resto del contexto; no es un MDT levantado"}; IncluirEnMediciones: no; Criterio: {"enabled":true,"basis":"Distribución aproximada autorizada. No acredita la posición ni el número real de plazas o farolas existentes.","pending":["Posición real del mobiliario","Dimensiones y niveles definitivos"]}

# IfcLightFixture: Luminaria del entorno · ilustrativa 25
In: Parcela industrial Jinhong
Description: Entorno de coordinación: trazados derivados de las fuentes indicadas por elemento; cotas, espesores, acabados y mobiliario orientativos cuando no están documentados. No acredita propiedad, servidumbres ni cantidades de obra y no es una base de construcción.; PredefinedType: USERDEFINED; Document: Indicación del cliente · entorno de 200 m con aparcamientos y luminarias ilustrativos; Entorno de Expacio Mérida · Catastro INSPIRE, PNOA y levantamiento Berrio; Levantamiento Berrio · parcelas I-27 Vial 3 e I-18 Vial 4; IGN · ortofotografía PNOA de máxima actualidad; Group: BIM · Entorno · aparcamientos y luminarias
JH_InformacionBIM - buildingId: context; buildingName: Entorno exterior de la parcela; level: Exterior · contexto de 200 m; category: Luminaria del entorno · ilustrativa 25; ifcClass: IfcLightFixture; status: provisional; source: {"documentId":"JH-CLIENT-CONTEXT-20260909","title":"Indicación del cliente · entorno de 200 m con aparcamientos y luminarias ilustrativos","date":"2026-09-09","note":"Distribución aproximada autorizada. No acredita la posición ni el número real de plazas o farolas existentes."}; material: {"name":"Luminaria exterior · gris","status":"provisional","source":"Acabado visual aproximado; no especificación de proyecto."}; appearance: {"profileId":"ctx_light","name":"Luminaria exterior · gris","status":"criterio_visual","basis":"Acabado de contexto orientativo, sin especificación de obra."}; dimensions: {"documented":[],"assumed":[{"label":"Altura de poste","value":8,"unit":"m"},{"label":"Vuelo de brazo","value":1.4,"unit":"m"}],"geometry":[]}; classification: {"layerId":"context_furniture","layerName":"Entorno · aparcamientos y luminarias","function":"Luminaria del entorno · ilustrativa 25"}; visualLayer: {"id":"context_furniture","name":"Entorno · aparcamientos y luminarias","defaultVisible":false}; representationKind: entorno_ilustrativo; quantityEligible: no; positioning: {"Sistema":"ETRS89 / UTM 29N · metros","Origen del modelo":"X 729400 · Y 4301550 · Z 285 m","Alcance":"Hasta 200 m desde el lindero del proyecto; solo exterior de parcela","Planta":"Distribución ilustrativa autorizada","Altimetría":"Plano ajustado a 213 puntos XYZ de aceras, extrapolado al resto del contexto; no es un MDT levantado"}; issues: ["Contexto para lectura del emplazamiento; planta derivada de cartografía, cotas y detalles simplificados. No para construcción ni mediciones de obra.","Las mediciones en el entorno expresan la geometría representada y conservan la precisión de su fuente."]; conceptual: {"enabled":true,"basis":"Distribución aproximada autorizada. No acredita la posición ni el número real de plazas o farolas existentes.","pending":["Posición real del mobiliario","Dimensiones y niveles definitivos"]}; geometryMetrics: {"boundingBoxM":{"min":[-83.250225,247.376424,0.265133],"max":[-82.540987,249.127884,8.375133]},"extentsM":[0.709238,1.75146,8.11],"meshSurfaceM2":5.532363,"meshVolumeM3":0.181319,"closedSolid":true,"basis":"Entorno de coordinación: trazados derivados de las fuentes indicadas por elemento; cotas, espesores, acabados y mobiliario orientativos cuando no están documentados. No acredita propiedad, servidumbres ni cantidades de obra y no es una base de construcción."}
JH_Trazabilidad - Origen: Indicación del cliente · entorno de 200 m con aparcamientos y luminarias ilustrativos; Estado: provisional; Capa BIM: Entorno · aparcamientos y luminarias; Mediciones de obra: Excluido; Identificador: CTX-LIGHT-25; Categoria: Luminaria del entorno · ilustrativa 25; ClaseIFC: IfcLightFixture; EstadoDeInformacion: provisional; DocumentoFuente: {"documentId":"JH-CLIENT-CONTEXT-20260909","title":"Indicación del cliente · entorno de 200 m con aparcamientos y luminarias ilustrativos","date":"2026-09-09","note":"Distribución aproximada autorizada. No acredita la posición ni el número real de plazas o farolas existentes."}; IncidenciasPendientes: ["Contexto para lectura del emplazamiento; planta derivada de cartografía, cotas y detalles simplificados. No para construcción ni mediciones de obra.","Las mediciones en el entorno expresan la geometría representada y conservan la precisión de su fuente."]; UsoDeLasMagnitudes: Entorno de coordinación: trazados derivados de las fuentes indicadas por elemento; cotas, espesores, acabados y mobiliario orientativos cuando no están documentados. No acredita propiedad, servidumbres ni cantidades de obra y no es una base de construcción.
JH_CriterioDePosicion - PosicionYEstado: {"Sistema":"ETRS89 / UTM 29N · metros","Origen del modelo":"X 729400 · Y 4301550 · Z 285 m","Alcance":"Hasta 200 m desde el lindero del proyecto; solo exterior de parcela","Planta":"Distribución ilustrativa autorizada","Altimetría":"Plano ajustado a 213 puntos XYZ de aceras, extrapolado al resto del contexto; no es un MDT levantado"}
JH_EvidenciaDeMaterial - name: Luminaria exterior · gris; status: provisional; source: Acabado visual aproximado; no especificación de proyecto.
JH_CapaBIM - IdentificadorCapa: context_furniture; NombreCapa: Entorno · aparcamientos y luminarias; Funcion: Luminaria del entorno · ilustrativa 25; VisibilidadInicial: no
JH_EntornoContexto - Estado: provisional; Origen: {"documentId":"JH-CLIENT-CONTEXT-20260909","title":"Indicación del cliente · entorno de 200 m con aparcamientos y luminarias ilustrativos","date":"2026-09-09","note":"Distribución aproximada autorizada. No acredita la posición ni el número real de plazas o farolas existentes."}; Posicion: {"Sistema":"ETRS89 / UTM 29N · metros","Origen del modelo":"X 729400 · Y 4301550 · Z 285 m","Alcance":"Hasta 200 m desde el lindero del proyecto; solo exterior de parcela","Planta":"Distribución ilustrativa autorizada","Altimetría":"Plano ajustado a 213 puntos XYZ de aceras, extrapolado al resto del contexto; no es un MDT levantado"}; DimensionesSupuestas: [{"label":"Altura de poste","value":8,"unit":"m"},{"label":"Vuelo de brazo","value":1.4,"unit":"m"}]; IncluirEnMediciones: no; EsquemaIlustrativo: yes; Criterio: Entorno de coordinación: trazados derivados de las fuentes indicadas por elemento; cotas, espesores, acabados y mobiliario orientativos cuando no están documentados. No acredita propiedad, servidumbres ni cantidades de obra y no es una base de construcción.
JH_EsquemaProvisional - Estado: No para construcción; Origen: {"documentId":"JH-CLIENT-CONTEXT-20260909","title":"Indicación del cliente · entorno de 200 m con aparcamientos y luminarias ilustrativos","date":"2026-09-09","note":"Distribución aproximada autorizada. No acredita la posición ni el número real de plazas o farolas existentes."}; DimensionesSupuestas: [{"label":"Altura de poste","value":8,"unit":"m"},{"label":"Vuelo de brazo","value":1.4,"unit":"m"}]; Posicion: {"Sistema":"ETRS89 / UTM 29N · metros","Origen del modelo":"X 729400 · Y 4301550 · Z 285 m","Alcance":"Hasta 200 m desde el lindero del proyecto; solo exterior de parcela","Planta":"Distribución ilustrativa autorizada","Altimetría":"Plano ajustado a 213 puntos XYZ de aceras, extrapolado al resto del contexto; no es un MDT levantado"}; IncluirEnMediciones: no; Criterio: {"enabled":true,"basis":"Distribución aproximada autorizada. No acredita la posición ni el número real de plazas o farolas existentes.","pending":["Posición real del mobiliario","Dimensiones y niveles definitivos"]}

# IfcLightFixture: Luminaria del entorno · ilustrativa 26
In: Parcela industrial Jinhong
Description: Entorno de coordinación: trazados derivados de las fuentes indicadas por elemento; cotas, espesores, acabados y mobiliario orientativos cuando no están documentados. No acredita propiedad, servidumbres ni cantidades de obra y no es una base de construcción.; PredefinedType: USERDEFINED; Document: Indicación del cliente · entorno de 200 m con aparcamientos y luminarias ilustrativos; Entorno de Expacio Mérida · Catastro INSPIRE, PNOA y levantamiento Berrio; Levantamiento Berrio · parcelas I-27 Vial 3 e I-18 Vial 4; IGN · ortofotografía PNOA de máxima actualidad; Group: BIM · Entorno · aparcamientos y luminarias
JH_InformacionBIM - buildingId: context; buildingName: Entorno exterior de la parcela; level: Exterior · contexto de 200 m; category: Luminaria del entorno · ilustrativa 26; ifcClass: IfcLightFixture; status: provisional; source: {"documentId":"JH-CLIENT-CONTEXT-20260909","title":"Indicación del cliente · entorno de 200 m con aparcamientos y luminarias ilustrativos","date":"2026-09-09","note":"Distribución aproximada autorizada. No acredita la posición ni el número real de plazas o farolas existentes."}; material: {"name":"Luminaria exterior · gris","status":"provisional","source":"Acabado visual aproximado; no especificación de proyecto."}; appearance: {"profileId":"ctx_light","name":"Luminaria exterior · gris","status":"criterio_visual","basis":"Acabado de contexto orientativo, sin especificación de obra."}; dimensions: {"documented":[],"assumed":[{"label":"Altura de poste","value":8,"unit":"m"},{"label":"Vuelo de brazo","value":1.4,"unit":"m"}],"geometry":[]}; classification: {"layerId":"context_furniture","layerName":"Entorno · aparcamientos y luminarias","function":"Luminaria del entorno · ilustrativa 26"}; visualLayer: {"id":"context_furniture","name":"Entorno · aparcamientos y luminarias","defaultVisible":false}; representationKind: entorno_ilustrativo; quantityEligible: no; positioning: {"Sistema":"ETRS89 / UTM 29N · metros","Origen del modelo":"X 729400 · Y 4301550 · Z 285 m","Alcance":"Hasta 200 m desde el lindero del proyecto; solo exterior de parcela","Planta":"Distribución ilustrativa autorizada","Altimetría":"Plano ajustado a 213 puntos XYZ de aceras, extrapolado al resto del contexto; no es un MDT levantado"}; issues: ["Contexto para lectura del emplazamiento; planta derivada de cartografía, cotas y detalles simplificados. No para construcción ni mediciones de obra.","Las mediciones en el entorno expresan la geometría representada y conservan la precisión de su fuente."]; conceptual: {"enabled":true,"basis":"Distribución aproximada autorizada. No acredita la posición ni el número real de plazas o farolas existentes.","pending":["Posición real del mobiliario","Dimensiones y niveles definitivos"]}; geometryMetrics: {"boundingBoxM":{"min":[-79.555325,274.299329,0.385409],"max":[-78.846087,276.050789,8.495409]},"extentsM":[0.709238,1.75146,8.11],"meshSurfaceM2":5.532365,"meshVolumeM3":0.181319,"closedSolid":true,"basis":"Entorno de coordinación: trazados derivados de las fuentes indicadas por elemento; cotas, espesores, acabados y mobiliario orientativos cuando no están documentados. No acredita propiedad, servidumbres ni cantidades de obra y no es una base de construcción."}
JH_Trazabilidad - Origen: Indicación del cliente · entorno de 200 m con aparcamientos y luminarias ilustrativos; Estado: provisional; Capa BIM: Entorno · aparcamientos y luminarias; Mediciones de obra: Excluido; Identificador: CTX-LIGHT-26; Categoria: Luminaria del entorno · ilustrativa 26; ClaseIFC: IfcLightFixture; EstadoDeInformacion: provisional; DocumentoFuente: {"documentId":"JH-CLIENT-CONTEXT-20260909","title":"Indicación del cliente · entorno de 200 m con aparcamientos y luminarias ilustrativos","date":"2026-09-09","note":"Distribución aproximada autorizada. No acredita la posición ni el número real de plazas o farolas existentes."}; IncidenciasPendientes: ["Contexto para lectura del emplazamiento; planta derivada de cartografía, cotas y detalles simplificados. No para construcción ni mediciones de obra.","Las mediciones en el entorno expresan la geometría representada y conservan la precisión de su fuente."]; UsoDeLasMagnitudes: Entorno de coordinación: trazados derivados de las fuentes indicadas por elemento; cotas, espesores, acabados y mobiliario orientativos cuando no están documentados. No acredita propiedad, servidumbres ni cantidades de obra y no es una base de construcción.
JH_CriterioDePosicion - PosicionYEstado: {"Sistema":"ETRS89 / UTM 29N · metros","Origen del modelo":"X 729400 · Y 4301550 · Z 285 m","Alcance":"Hasta 200 m desde el lindero del proyecto; solo exterior de parcela","Planta":"Distribución ilustrativa autorizada","Altimetría":"Plano ajustado a 213 puntos XYZ de aceras, extrapolado al resto del contexto; no es un MDT levantado"}
JH_EvidenciaDeMaterial - name: Luminaria exterior · gris; status: provisional; source: Acabado visual aproximado; no especificación de proyecto.
JH_CapaBIM - IdentificadorCapa: context_furniture; NombreCapa: Entorno · aparcamientos y luminarias; Funcion: Luminaria del entorno · ilustrativa 26; VisibilidadInicial: no
JH_EntornoContexto - Estado: provisional; Origen: {"documentId":"JH-CLIENT-CONTEXT-20260909","title":"Indicación del cliente · entorno de 200 m con aparcamientos y luminarias ilustrativos","date":"2026-09-09","note":"Distribución aproximada autorizada. No acredita la posición ni el número real de plazas o farolas existentes."}; Posicion: {"Sistema":"ETRS89 / UTM 29N · metros","Origen del modelo":"X 729400 · Y 4301550 · Z 285 m","Alcance":"Hasta 200 m desde el lindero del proyecto; solo exterior de parcela","Planta":"Distribución ilustrativa autorizada","Altimetría":"Plano ajustado a 213 puntos XYZ de aceras, extrapolado al resto del contexto; no es un MDT levantado"}; DimensionesSupuestas: [{"label":"Altura de poste","value":8,"unit":"m"},{"label":"Vuelo de brazo","value":1.4,"unit":"m"}]; IncluirEnMediciones: no; EsquemaIlustrativo: yes; Criterio: Entorno de coordinación: trazados derivados de las fuentes indicadas por elemento; cotas, espesores, acabados y mobiliario orientativos cuando no están documentados. No acredita propiedad, servidumbres ni cantidades de obra y no es una base de construcción.
JH_EsquemaProvisional - Estado: No para construcción; Origen: {"documentId":"JH-CLIENT-CONTEXT-20260909","title":"Indicación del cliente · entorno de 200 m con aparcamientos y luminarias ilustrativos","date":"2026-09-09","note":"Distribución aproximada autorizada. No acredita la posición ni el número real de plazas o farolas existentes."}; DimensionesSupuestas: [{"label":"Altura de poste","value":8,"unit":"m"},{"label":"Vuelo de brazo","value":1.4,"unit":"m"}]; Posicion: {"Sistema":"ETRS89 / UTM 29N · metros","Origen del modelo":"X 729400 · Y 4301550 · Z 285 m","Alcance":"Hasta 200 m desde el lindero del proyecto; solo exterior de parcela","Planta":"Distribución ilustrativa autorizada","Altimetría":"Plano ajustado a 213 puntos XYZ de aceras, extrapolado al resto del contexto; no es un MDT levantado"}; IncluirEnMediciones: no; Criterio: {"enabled":true,"basis":"Distribución aproximada autorizada. No acredita la posición ni el número real de plazas o farolas existentes.","pending":["Posición real del mobiliario","Dimensiones y niveles definitivos"]}

# IfcLightFixture: Luminaria del entorno · ilustrativa 27
In: Parcela industrial Jinhong
Description: Entorno de coordinación: trazados derivados de las fuentes indicadas por elemento; cotas, espesores, acabados y mobiliario orientativos cuando no están documentados. No acredita propiedad, servidumbres ni cantidades de obra y no es una base de construcción.; PredefinedType: USERDEFINED; Document: Indicación del cliente · entorno de 200 m con aparcamientos y luminarias ilustrativos; Entorno de Expacio Mérida · Catastro INSPIRE, PNOA y levantamiento Berrio; Levantamiento Berrio · parcelas I-27 Vial 3 e I-18 Vial 4; IGN · ortofotografía PNOA de máxima actualidad; Group: BIM · Entorno · aparcamientos y luminarias
JH_InformacionBIM - buildingId: context; buildingName: Entorno exterior de la parcela; level: Exterior · contexto de 200 m; category: Luminaria del entorno · ilustrativa 27; ifcClass: IfcLightFixture; status: provisional; source: {"documentId":"JH-CLIENT-CONTEXT-20260909","title":"Indicación del cliente · entorno de 200 m con aparcamientos y luminarias ilustrativos","date":"2026-09-09","note":"Distribución aproximada autorizada. No acredita la posición ni el número real de plazas o farolas existentes."}; material: {"name":"Luminaria exterior · gris","status":"provisional","source":"Acabado visual aproximado; no especificación de proyecto."}; appearance: {"profileId":"ctx_light","name":"Luminaria exterior · gris","status":"criterio_visual","basis":"Acabado de contexto orientativo, sin especificación de obra."}; dimensions: {"documented":[],"assumed":[{"label":"Altura de poste","value":8,"unit":"m"},{"label":"Vuelo de brazo","value":1.4,"unit":"m"}],"geometry":[]}; classification: {"layerId":"context_furniture","layerName":"Entorno · aparcamientos y luminarias","function":"Luminaria del entorno · ilustrativa 27"}; visualLayer: {"id":"context_furniture","name":"Entorno · aparcamientos y luminarias","defaultVisible":false}; representationKind: entorno_ilustrativo; quantityEligible: no; positioning: {"Sistema":"ETRS89 / UTM 29N · metros","Origen del modelo":"X 729400 · Y 4301550 · Z 285 m","Alcance":"Hasta 200 m desde el lindero del proyecto; solo exterior de parcela","Planta":"Distribución ilustrativa autorizada","Altimetría":"Plano ajustado a 213 puntos XYZ de aceras, extrapolado al resto del contexto; no es un MDT levantado"}; issues: ["Contexto para lectura del emplazamiento; planta derivada de cartografía, cotas y detalles simplificados. No para construcción ni mediciones de obra.","Las mediciones en el entorno expresan la geometría representada y conservan la precisión de su fuente."]; conceptual: {"enabled":true,"basis":"Distribución aproximada autorizada. No acredita la posición ni el número real de plazas o farolas existentes.","pending":["Posición real del mobiliario","Dimensiones y niveles definitivos"]}; geometryMetrics: {"boundingBoxM":{"min":[-51.55971,242.93669,0.613668],"max":[-50.850471,244.68815,8.723668]},"extentsM":[0.709239,1.75146,8.11],"meshSurfaceM2":5.532364,"meshVolumeM3":0.181319,"closedSolid":true,"basis":"Entorno de coordinación: trazados derivados de las fuentes indicadas por elemento; cotas, espesores, acabados y mobiliario orientativos cuando no están documentados. No acredita propiedad, servidumbres ni cantidades de obra y no es una base de construcción."}
JH_Trazabilidad - Origen: Indicación del cliente · entorno de 200 m con aparcamientos y luminarias ilustrativos; Estado: provisional; Capa BIM: Entorno · aparcamientos y luminarias; Mediciones de obra: Excluido; Identificador: CTX-LIGHT-27; Categoria: Luminaria del entorno · ilustrativa 27; ClaseIFC: IfcLightFixture; EstadoDeInformacion: provisional; DocumentoFuente: {"documentId":"JH-CLIENT-CONTEXT-20260909","title":"Indicación del cliente · entorno de 200 m con aparcamientos y luminarias ilustrativos","date":"2026-09-09","note":"Distribución aproximada autorizada. No acredita la posición ni el número real de plazas o farolas existentes."}; IncidenciasPendientes: ["Contexto para lectura del emplazamiento; planta derivada de cartografía, cotas y detalles simplificados. No para construcción ni mediciones de obra.","Las mediciones en el entorno expresan la geometría representada y conservan la precisión de su fuente."]; UsoDeLasMagnitudes: Entorno de coordinación: trazados derivados de las fuentes indicadas por elemento; cotas, espesores, acabados y mobiliario orientativos cuando no están documentados. No acredita propiedad, servidumbres ni cantidades de obra y no es una base de construcción.
JH_CriterioDePosicion - PosicionYEstado: {"Sistema":"ETRS89 / UTM 29N · metros","Origen del modelo":"X 729400 · Y 4301550 · Z 285 m","Alcance":"Hasta 200 m desde el lindero del proyecto; solo exterior de parcela","Planta":"Distribución ilustrativa autorizada","Altimetría":"Plano ajustado a 213 puntos XYZ de aceras, extrapolado al resto del contexto; no es un MDT levantado"}
JH_EvidenciaDeMaterial - name: Luminaria exterior · gris; status: provisional; source: Acabado visual aproximado; no especificación de proyecto.
JH_CapaBIM - IdentificadorCapa: context_furniture; NombreCapa: Entorno · aparcamientos y luminarias; Funcion: Luminaria del entorno · ilustrativa 27; VisibilidadInicial: no
JH_EntornoContexto - Estado: provisional; Origen: {"documentId":"JH-CLIENT-CONTEXT-20260909","title":"Indicación del cliente · entorno de 200 m con aparcamientos y luminarias ilustrativos","date":"2026-09-09","note":"Distribución aproximada autorizada. No acredita la posición ni el número real de plazas o farolas existentes."}; Posicion: {"Sistema":"ETRS89 / UTM 29N · metros","Origen del modelo":"X 729400 · Y 4301550 · Z 285 m","Alcance":"Hasta 200 m desde el lindero del proyecto; solo exterior de parcela","Planta":"Distribución ilustrativa autorizada","Altimetría":"Plano ajustado a 213 puntos XYZ de aceras, extrapolado al resto del contexto; no es un MDT levantado"}; DimensionesSupuestas: [{"label":"Altura de poste","value":8,"unit":"m"},{"label":"Vuelo de brazo","value":1.4,"unit":"m"}]; IncluirEnMediciones: no; EsquemaIlustrativo: yes; Criterio: Entorno de coordinación: trazados derivados de las fuentes indicadas por elemento; cotas, espesores, acabados y mobiliario orientativos cuando no están documentados. No acredita propiedad, servidumbres ni cantidades de obra y no es una base de construcción.
JH_EsquemaProvisional - Estado: No para construcción; Origen: {"documentId":"JH-CLIENT-CONTEXT-20260909","title":"Indicación del cliente · entorno de 200 m con aparcamientos y luminarias ilustrativos","date":"2026-09-09","note":"Distribución aproximada autorizada. No acredita la posición ni el número real de plazas o farolas existentes."}; DimensionesSupuestas: [{"label":"Altura de poste","value":8,"unit":"m"},{"label":"Vuelo de brazo","value":1.4,"unit":"m"}]; Posicion: {"Sistema":"ETRS89 / UTM 29N · metros","Origen del modelo":"X 729400 · Y 4301550 · Z 285 m","Alcance":"Hasta 200 m desde el lindero del proyecto; solo exterior de parcela","Planta":"Distribución ilustrativa autorizada","Altimetría":"Plano ajustado a 213 puntos XYZ de aceras, extrapolado al resto del contexto; no es un MDT levantado"}; IncluirEnMediciones: no; Criterio: {"enabled":true,"basis":"Distribución aproximada autorizada. No acredita la posición ni el número real de plazas o farolas existentes.","pending":["Posición real del mobiliario","Dimensiones y niveles definitivos"]}

# IfcLightFixture: Luminaria del entorno · ilustrativa 28
In: Parcela industrial Jinhong
Description: Entorno de coordinación: trazados derivados de las fuentes indicadas por elemento; cotas, espesores, acabados y mobiliario orientativos cuando no están documentados. No acredita propiedad, servidumbres ni cantidades de obra y no es una base de construcción.; PredefinedType: USERDEFINED; Document: Indicación del cliente · entorno de 200 m con aparcamientos y luminarias ilustrativos; Entorno de Expacio Mérida · Catastro INSPIRE, PNOA y levantamiento Berrio; Levantamiento Berrio · parcelas I-27 Vial 3 e I-18 Vial 4; IGN · ortofotografía PNOA de máxima actualidad; Group: BIM · Entorno · aparcamientos y luminarias
JH_InformacionBIM - buildingId: context; buildingName: Entorno exterior de la parcela; level: Exterior · contexto de 200 m; category: Luminaria del entorno · ilustrativa 28; ifcClass: IfcLightFixture; status: provisional; source: {"documentId":"JH-CLIENT-CONTEXT-20260909","title":"Indicación del cliente · entorno de 200 m con aparcamientos y luminarias ilustrativos","date":"2026-09-09","note":"Distribución aproximada autorizada. No acredita la posición ni el número real de plazas o farolas existentes."}; material: {"name":"Luminaria exterior · gris","status":"provisional","source":"Acabado visual aproximado; no especificación de proyecto."}; appearance: {"profileId":"ctx_light","name":"Luminaria exterior · gris","status":"criterio_visual","basis":"Acabado de contexto orientativo, sin especificación de obra."}; dimensions: {"documented":[],"assumed":[{"label":"Altura de poste","value":8,"unit":"m"},{"label":"Vuelo de brazo","value":1.4,"unit":"m"}],"geometry":[]}; classification: {"layerId":"context_furniture","layerName":"Entorno · aparcamientos y luminarias","function":"Luminaria del entorno · ilustrativa 28"}; visualLayer: {"id":"context_furniture","name":"Entorno · aparcamientos y luminarias","defaultVisible":false}; representationKind: entorno_ilustrativo; quantityEligible: no; positioning: {"Sistema":"ETRS89 / UTM 29N · metros","Origen del modelo":"X 729400 · Y 4301550 · Z 285 m","Alcance":"Hasta 200 m desde el lindero del proyecto; solo exterior de parcela","Planta":"Distribución ilustrativa autorizada","Altimetría":"Plano ajustado a 213 puntos XYZ de aceras, extrapolado al resto del contexto; no es un MDT levantado"}; issues: ["Contexto para lectura del emplazamiento; planta derivada de cartografía, cotas y detalles simplificados. No para construcción ni mediciones de obra.","Las mediciones en el entorno expresan la geometría representada y conservan la precisión de su fuente."]; conceptual: {"enabled":true,"basis":"Distribución aproximada autorizada. No acredita la posición ni el número real de plazas o farolas existentes.","pending":["Posición real del mobiliario","Dimensiones y niveles definitivos"]}; geometryMetrics: {"boundingBoxM":{"min":[-47.86481,269.859595,0.733944],"max":[-47.155572,271.611055,8.843944]},"extentsM":[0.709238,1.75146,8.11],"meshSurfaceM2":5.532365,"meshVolumeM3":0.181319,"closedSolid":true,"basis":"Entorno de coordinación: trazados derivados de las fuentes indicadas por elemento; cotas, espesores, acabados y mobiliario orientativos cuando no están documentados. No acredita propiedad, servidumbres ni cantidades de obra y no es una base de construcción."}
JH_Trazabilidad - Origen: Indicación del cliente · entorno de 200 m con aparcamientos y luminarias ilustrativos; Estado: provisional; Capa BIM: Entorno · aparcamientos y luminarias; Mediciones de obra: Excluido; Identificador: CTX-LIGHT-28; Categoria: Luminaria del entorno · ilustrativa 28; ClaseIFC: IfcLightFixture; EstadoDeInformacion: provisional; DocumentoFuente: {"documentId":"JH-CLIENT-CONTEXT-20260909","title":"Indicación del cliente · entorno de 200 m con aparcamientos y luminarias ilustrativos","date":"2026-09-09","note":"Distribución aproximada autorizada. No acredita la posición ni el número real de plazas o farolas existentes."}; IncidenciasPendientes: ["Contexto para lectura del emplazamiento; planta derivada de cartografía, cotas y detalles simplificados. No para construcción ni mediciones de obra.","Las mediciones en el entorno expresan la geometría representada y conservan la precisión de su fuente."]; UsoDeLasMagnitudes: Entorno de coordinación: trazados derivados de las fuentes indicadas por elemento; cotas, espesores, acabados y mobiliario orientativos cuando no están documentados. No acredita propiedad, servidumbres ni cantidades de obra y no es una base de construcción.
JH_CriterioDePosicion - PosicionYEstado: {"Sistema":"ETRS89 / UTM 29N · metros","Origen del modelo":"X 729400 · Y 4301550 · Z 285 m","Alcance":"Hasta 200 m desde el lindero del proyecto; solo exterior de parcela","Planta":"Distribución ilustrativa autorizada","Altimetría":"Plano ajustado a 213 puntos XYZ de aceras, extrapolado al resto del contexto; no es un MDT levantado"}
JH_EvidenciaDeMaterial - name: Luminaria exterior · gris; status: provisional; source: Acabado visual aproximado; no especificación de proyecto.
JH_CapaBIM - IdentificadorCapa: context_furniture; NombreCapa: Entorno · aparcamientos y luminarias; Funcion: Luminaria del entorno · ilustrativa 28; VisibilidadInicial: no
JH_EntornoContexto - Estado: provisional; Origen: {"documentId":"JH-CLIENT-CONTEXT-20260909","title":"Indicación del cliente · entorno de 200 m con aparcamientos y luminarias ilustrativos","date":"2026-09-09","note":"Distribución aproximada autorizada. No acredita la posición ni el número real de plazas o farolas existentes."}; Posicion: {"Sistema":"ETRS89 / UTM 29N · metros","Origen del modelo":"X 729400 · Y 4301550 · Z 285 m","Alcance":"Hasta 200 m desde el lindero del proyecto; solo exterior de parcela","Planta":"Distribución ilustrativa autorizada","Altimetría":"Plano ajustado a 213 puntos XYZ de aceras, extrapolado al resto del contexto; no es un MDT levantado"}; DimensionesSupuestas: [{"label":"Altura de poste","value":8,"unit":"m"},{"label":"Vuelo de brazo","value":1.4,"unit":"m"}]; IncluirEnMediciones: no; EsquemaIlustrativo: yes; Criterio: Entorno de coordinación: trazados derivados de las fuentes indicadas por elemento; cotas, espesores, acabados y mobiliario orientativos cuando no están documentados. No acredita propiedad, servidumbres ni cantidades de obra y no es una base de construcción.
JH_EsquemaProvisional - Estado: No para construcción; Origen: {"documentId":"JH-CLIENT-CONTEXT-20260909","title":"Indicación del cliente · entorno de 200 m con aparcamientos y luminarias ilustrativos","date":"2026-09-09","note":"Distribución aproximada autorizada. No acredita la posición ni el número real de plazas o farolas existentes."}; DimensionesSupuestas: [{"label":"Altura de poste","value":8,"unit":"m"},{"label":"Vuelo de brazo","value":1.4,"unit":"m"}]; Posicion: {"Sistema":"ETRS89 / UTM 29N · metros","Origen del modelo":"X 729400 · Y 4301550 · Z 285 m","Alcance":"Hasta 200 m desde el lindero del proyecto; solo exterior de parcela","Planta":"Distribución ilustrativa autorizada","Altimetría":"Plano ajustado a 213 puntos XYZ de aceras, extrapolado al resto del contexto; no es un MDT levantado"}; IncluirEnMediciones: no; Criterio: {"enabled":true,"basis":"Distribución aproximada autorizada. No acredita la posición ni el número real de plazas o farolas existentes.","pending":["Posición real del mobiliario","Dimensiones y niveles definitivos"]}

# IfcLightFixture: Luminaria del entorno · ilustrativa 29
In: Parcela industrial Jinhong
Description: Entorno de coordinación: trazados derivados de las fuentes indicadas por elemento; cotas, espesores, acabados y mobiliario orientativos cuando no están documentados. No acredita propiedad, servidumbres ni cantidades de obra y no es una base de construcción.; PredefinedType: USERDEFINED; Document: Indicación del cliente · entorno de 200 m con aparcamientos y luminarias ilustrativos; Entorno de Expacio Mérida · Catastro INSPIRE, PNOA y levantamiento Berrio; Levantamiento Berrio · parcelas I-27 Vial 3 e I-18 Vial 4; IGN · ortofotografía PNOA de máxima actualidad; Group: BIM · Entorno · aparcamientos y luminarias
JH_InformacionBIM - buildingId: context; buildingName: Entorno exterior de la parcela; level: Exterior · contexto de 200 m; category: Luminaria del entorno · ilustrativa 29; ifcClass: IfcLightFixture; status: provisional; source: {"documentId":"JH-CLIENT-CONTEXT-20260909","title":"Indicación del cliente · entorno de 200 m con aparcamientos y luminarias ilustrativos","date":"2026-09-09","note":"Distribución aproximada autorizada. No acredita la posición ni el número real de plazas o farolas existentes."}; material: {"name":"Luminaria exterior · gris","status":"provisional","source":"Acabado visual aproximado; no especificación de proyecto."}; appearance: {"profileId":"ctx_light","name":"Luminaria exterior · gris","status":"criterio_visual","basis":"Acabado de contexto orientativo, sin especificación de obra."}; dimensions: {"documented":[],"assumed":[{"label":"Altura de poste","value":8,"unit":"m"},{"label":"Vuelo de brazo","value":1.4,"unit":"m"}],"geometry":[]}; classification: {"layerId":"context_furniture","layerName":"Entorno · aparcamientos y luminarias","function":"Luminaria del entorno · ilustrativa 29"}; visualLayer: {"id":"context_furniture","name":"Entorno · aparcamientos y luminarias","defaultVisible":false}; representationKind: entorno_ilustrativo; quantityEligible: no; positioning: {"Sistema":"ETRS89 / UTM 29N · metros","Origen del modelo":"X 729400 · Y 4301550 · Z 285 m","Alcance":"Hasta 200 m desde el lindero del proyecto; solo exterior de parcela","Planta":"Distribución ilustrativa autorizada","Altimetría":"Plano ajustado a 213 puntos XYZ de aceras, extrapolado al resto del contexto; no es un MDT levantado"}; issues: ["Contexto para lectura del emplazamiento; planta derivada de cartografía, cotas y detalles simplificados. No para construcción ni mediciones de obra.","Las mediciones en el entorno expresan la geometría representada y conservan la precisión de su fuente."]; conceptual: {"enabled":true,"basis":"Distribución aproximada autorizada. No acredita la posición ni el número real de plazas o farolas existentes.","pending":["Posición real del mobiliario","Dimensiones y niveles definitivos"]}; geometryMetrics: {"boundingBoxM":{"min":[136.41524,-46.226429,1.996236],"max":[138.316169,-45.663439,10.106236]},"extentsM":[1.900929,0.56299,8.11],"meshSurfaceM2":5.532366,"meshVolumeM3":0.181319,"closedSolid":true,"basis":"Entorno de coordinación: trazados derivados de las fuentes indicadas por elemento; cotas, espesores, acabados y mobiliario orientativos cuando no están documentados. No acredita propiedad, servidumbres ni cantidades de obra y no es una base de construcción."}
JH_Trazabilidad - Origen: Indicación del cliente · entorno de 200 m con aparcamientos y luminarias ilustrativos; Estado: provisional; Capa BIM: Entorno · aparcamientos y luminarias; Mediciones de obra: Excluido; Identificador: CTX-LIGHT-29; Categoria: Luminaria del entorno · ilustrativa 29; ClaseIFC: IfcLightFixture; EstadoDeInformacion: provisional; DocumentoFuente: {"documentId":"JH-CLIENT-CONTEXT-20260909","title":"Indicación del cliente · entorno de 200 m con aparcamientos y luminarias ilustrativos","date":"2026-09-09","note":"Distribución aproximada autorizada. No acredita la posición ni el número real de plazas o farolas existentes."}; IncidenciasPendientes: ["Contexto para lectura del emplazamiento; planta derivada de cartografía, cotas y detalles simplificados. No para construcción ni mediciones de obra.","Las mediciones en el entorno expresan la geometría representada y conservan la precisión de su fuente."]; UsoDeLasMagnitudes: Entorno de coordinación: trazados derivados de las fuentes indicadas por elemento; cotas, espesores, acabados y mobiliario orientativos cuando no están documentados. No acredita propiedad, servidumbres ni cantidades de obra y no es una base de construcción.
JH_CriterioDePosicion - PosicionYEstado: {"Sistema":"ETRS89 / UTM 29N · metros","Origen del modelo":"X 729400 · Y 4301550 · Z 285 m","Alcance":"Hasta 200 m desde el lindero del proyecto; solo exterior de parcela","Planta":"Distribución ilustrativa autorizada","Altimetría":"Plano ajustado a 213 puntos XYZ de aceras, extrapolado al resto del contexto; no es un MDT levantado"}
JH_EvidenciaDeMaterial - name: Luminaria exterior · gris; status: provisional; source: Acabado visual aproximado; no especificación de proyecto.
JH_CapaBIM - IdentificadorCapa: context_furniture; NombreCapa: Entorno · aparcamientos y luminarias; Funcion: Luminaria del entorno · ilustrativa 29; VisibilidadInicial: no
JH_EntornoContexto - Estado: provisional; Origen: {"documentId":"JH-CLIENT-CONTEXT-20260909","title":"Indicación del cliente · entorno de 200 m con aparcamientos y luminarias ilustrativos","date":"2026-09-09","note":"Distribución aproximada autorizada. No acredita la posición ni el número real de plazas o farolas existentes."}; Posicion: {"Sistema":"ETRS89 / UTM 29N · metros","Origen del modelo":"X 729400 · Y 4301550 · Z 285 m","Alcance":"Hasta 200 m desde el lindero del proyecto; solo exterior de parcela","Planta":"Distribución ilustrativa autorizada","Altimetría":"Plano ajustado a 213 puntos XYZ de aceras, extrapolado al resto del contexto; no es un MDT levantado"}; DimensionesSupuestas: [{"label":"Altura de poste","value":8,"unit":"m"},{"label":"Vuelo de brazo","value":1.4,"unit":"m"}]; IncluirEnMediciones: no; EsquemaIlustrativo: yes; Criterio: Entorno de coordinación: trazados derivados de las fuentes indicadas por elemento; cotas, espesores, acabados y mobiliario orientativos cuando no están documentados. No acredita propiedad, servidumbres ni cantidades de obra y no es una base de construcción.
JH_EsquemaProvisional - Estado: No para construcción; Origen: {"documentId":"JH-CLIENT-CONTEXT-20260909","title":"Indicación del cliente · entorno de 200 m con aparcamientos y luminarias ilustrativos","date":"2026-09-09","note":"Distribución aproximada autorizada. No acredita la posición ni el número real de plazas o farolas existentes."}; DimensionesSupuestas: [{"label":"Altura de poste","value":8,"unit":"m"},{"label":"Vuelo de brazo","value":1.4,"unit":"m"}]; Posicion: {"Sistema":"ETRS89 / UTM 29N · metros","Origen del modelo":"X 729400 · Y 4301550 · Z 285 m","Alcance":"Hasta 200 m desde el lindero del proyecto; solo exterior de parcela","Planta":"Distribución ilustrativa autorizada","Altimetría":"Plano ajustado a 213 puntos XYZ de aceras, extrapolado al resto del contexto; no es un MDT levantado"}; IncluirEnMediciones: no; Criterio: {"enabled":true,"basis":"Distribución aproximada autorizada. No acredita la posición ni el número real de plazas o farolas existentes.","pending":["Posición real del mobiliario","Dimensiones y niveles definitivos"]}

# IfcLightFixture: Luminaria del entorno · ilustrativa 3
In: Parcela industrial Jinhong
Description: Entorno de coordinación: trazados derivados de las fuentes indicadas por elemento; cotas, espesores, acabados y mobiliario orientativos cuando no están documentados. No acredita propiedad, servidumbres ni cantidades de obra y no es una base de construcción.; PredefinedType: USERDEFINED; Document: Indicación del cliente · entorno de 200 m con aparcamientos y luminarias ilustrativos; Entorno de Expacio Mérida · Catastro INSPIRE, PNOA y levantamiento Berrio; Levantamiento Berrio · parcelas I-27 Vial 3 e I-18 Vial 4; IGN · ortofotografía PNOA de máxima actualidad; Group: BIM · Entorno · aparcamientos y luminarias
JH_InformacionBIM - buildingId: context; buildingName: Entorno exterior de la parcela; level: Exterior · contexto de 200 m; category: Luminaria del entorno · ilustrativa 3; ifcClass: IfcLightFixture; status: provisional; source: {"documentId":"JH-CLIENT-CONTEXT-20260909","title":"Indicación del cliente · entorno de 200 m con aparcamientos y luminarias ilustrativos","date":"2026-09-09","note":"Distribución aproximada autorizada. No acredita la posición ni el número real de plazas o farolas existentes."}; material: {"name":"Luminaria exterior · gris","status":"provisional","source":"Acabado visual aproximado; no especificación de proyecto."}; appearance: {"profileId":"ctx_light","name":"Luminaria exterior · gris","status":"criterio_visual","basis":"Acabado de contexto orientativo, sin especificación de obra."}; dimensions: {"documented":[],"assumed":[{"label":"Altura de poste","value":8,"unit":"m"},{"label":"Vuelo de brazo","value":1.4,"unit":"m"}],"geometry":[]}; classification: {"layerId":"context_furniture","layerName":"Entorno · aparcamientos y luminarias","function":"Luminaria del entorno · ilustrativa 3"}; visualLayer: {"id":"context_furniture","name":"Entorno · aparcamientos y luminarias","defaultVisible":false}; representationKind: entorno_ilustrativo; quantityEligible: no; positioning: {"Sistema":"ETRS89 / UTM 29N · metros","Origen del modelo":"X 729400 · Y 4301550 · Z 285 m","Alcance":"Hasta 200 m desde el lindero del proyecto; solo exterior de parcela","Planta":"Distribución ilustrativa autorizada","Altimetría":"Plano ajustado a 213 puntos XYZ de aceras, extrapolado al resto del contexto; no es un MDT levantado"}; issues: ["Contexto para lectura del emplazamiento; planta derivada de cartografía, cotas y detalles simplificados. No para construcción ni mediciones de obra.","Las mediciones en el entorno expresan la geometría representada y conservan la precisión de su fuente."]; conceptual: {"enabled":true,"basis":"Distribución aproximada autorizada. No acredita la posición ni el número real de plazas o farolas existentes.","pending":["Posición real del mobiliario","Dimensiones y niveles definitivos"]}; geometryMetrics: {"boundingBoxM":{"min":[-18.284904,-47.395214,0.233988],"max":[-16.374821,-46.91298,8.343988]},"extentsM":[1.910083,0.482234,8.11],"meshSurfaceM2":5.532365,"meshVolumeM3":0.181319,"closedSolid":true,"basis":"Entorno de coordinación: trazados derivados de las fuentes indicadas por elemento; cotas, espesores, acabados y mobiliario orientativos cuando no están documentados. No acredita propiedad, servidumbres ni cantidades de obra y no es una base de construcción."}
JH_Trazabilidad - Origen: Indicación del cliente · entorno de 200 m con aparcamientos y luminarias ilustrativos; Estado: provisional; Capa BIM: Entorno · aparcamientos y luminarias; Mediciones de obra: Excluido; Identificador: CTX-LIGHT-03; Categoria: Luminaria del entorno · ilustrativa 3; ClaseIFC: IfcLightFixture; EstadoDeInformacion: provisional; DocumentoFuente: {"documentId":"JH-CLIENT-CONTEXT-20260909","title":"Indicación del cliente · entorno de 200 m con aparcamientos y luminarias ilustrativos","date":"2026-09-09","note":"Distribución aproximada autorizada. No acredita la posición ni el número real de plazas o farolas existentes."}; IncidenciasPendientes: ["Contexto para lectura del emplazamiento; planta derivada de cartografía, cotas y detalles simplificados. No para construcción ni mediciones de obra.","Las mediciones en el entorno expresan la geometría representada y conservan la precisión de su fuente."]; UsoDeLasMagnitudes: Entorno de coordinación: trazados derivados de las fuentes indicadas por elemento; cotas, espesores, acabados y mobiliario orientativos cuando no están documentados. No acredita propiedad, servidumbres ni cantidades de obra y no es una base de construcción.
JH_CriterioDePosicion - PosicionYEstado: {"Sistema":"ETRS89 / UTM 29N · metros","Origen del modelo":"X 729400 · Y 4301550 · Z 285 m","Alcance":"Hasta 200 m desde el lindero del proyecto; solo exterior de parcela","Planta":"Distribución ilustrativa autorizada","Altimetría":"Plano ajustado a 213 puntos XYZ de aceras, extrapolado al resto del contexto; no es un MDT levantado"}
JH_EvidenciaDeMaterial - name: Luminaria exterior · gris; status: provisional; source: Acabado visual aproximado; no especificación de proyecto.
JH_CapaBIM - IdentificadorCapa: context_furniture; NombreCapa: Entorno · aparcamientos y luminarias; Funcion: Luminaria del entorno · ilustrativa 3; VisibilidadInicial: no
JH_EntornoContexto - Estado: provisional; Origen: {"documentId":"JH-CLIENT-CONTEXT-20260909","title":"Indicación del cliente · entorno de 200 m con aparcamientos y luminarias ilustrativos","date":"2026-09-09","note":"Distribución aproximada autorizada. No acredita la posición ni el número real de plazas o farolas existentes."}; Posicion: {"Sistema":"ETRS89 / UTM 29N · metros","Origen del modelo":"X 729400 · Y 4301550 · Z 285 m","Alcance":"Hasta 200 m desde el lindero del proyecto; solo exterior de parcela","Planta":"Distribución ilustrativa autorizada","Altimetría":"Plano ajustado a 213 puntos XYZ de aceras, extrapolado al resto del contexto; no es un MDT levantado"}; DimensionesSupuestas: [{"label":"Altura de poste","value":8,"unit":"m"},{"label":"Vuelo de brazo","value":1.4,"unit":"m"}]; IncluirEnMediciones: no; EsquemaIlustrativo: yes; Criterio: Entorno de coordinación: trazados derivados de las fuentes indicadas por elemento; cotas, espesores, acabados y mobiliario orientativos cuando no están documentados. No acredita propiedad, servidumbres ni cantidades de obra y no es una base de construcción.
JH_EsquemaProvisional - Estado: No para construcción; Origen: {"documentId":"JH-CLIENT-CONTEXT-20260909","title":"Indicación del cliente · entorno de 200 m con aparcamientos y luminarias ilustrativos","date":"2026-09-09","note":"Distribución aproximada autorizada. No acredita la posición ni el número real de plazas o farolas existentes."}; DimensionesSupuestas: [{"label":"Altura de poste","value":8,"unit":"m"},{"label":"Vuelo de brazo","value":1.4,"unit":"m"}]; Posicion: {"Sistema":"ETRS89 / UTM 29N · metros","Origen del modelo":"X 729400 · Y 4301550 · Z 285 m","Alcance":"Hasta 200 m desde el lindero del proyecto; solo exterior de parcela","Planta":"Distribución ilustrativa autorizada","Altimetría":"Plano ajustado a 213 puntos XYZ de aceras, extrapolado al resto del contexto; no es un MDT levantado"}; IncluirEnMediciones: no; Criterio: {"enabled":true,"basis":"Distribución aproximada autorizada. No acredita la posición ni el número real de plazas o farolas existentes.","pending":["Posición real del mobiliario","Dimensiones y niveles definitivos"]}

# IfcLightFixture: Luminaria del entorno · ilustrativa 30
In: Parcela industrial Jinhong
Description: Entorno de coordinación: trazados derivados de las fuentes indicadas por elemento; cotas, espesores, acabados y mobiliario orientativos cuando no están documentados. No acredita propiedad, servidumbres ni cantidades de obra y no es una base de construcción.; PredefinedType: USERDEFINED; Document: Indicación del cliente · entorno de 200 m con aparcamientos y luminarias ilustrativos; Entorno de Expacio Mérida · Catastro INSPIRE, PNOA y levantamiento Berrio; Levantamiento Berrio · parcelas I-27 Vial 3 e I-18 Vial 4; IGN · ortofotografía PNOA de máxima actualidad; Group: BIM · Entorno · aparcamientos y luminarias
JH_InformacionBIM - buildingId: context; buildingName: Entorno exterior de la parcela; level: Exterior · contexto de 200 m; category: Luminaria del entorno · ilustrativa 30; ifcClass: IfcLightFixture; status: provisional; source: {"documentId":"JH-CLIENT-CONTEXT-20260909","title":"Indicación del cliente · entorno de 200 m con aparcamientos y luminarias ilustrativos","date":"2026-09-09","note":"Distribución aproximada autorizada. No acredita la posición ni el número real de plazas o farolas existentes."}; material: {"name":"Luminaria exterior · gris","status":"provisional","source":"Acabado visual aproximado; no especificación de proyecto."}; appearance: {"profileId":"ctx_light","name":"Luminaria exterior · gris","status":"criterio_visual","basis":"Acabado de contexto orientativo, sin especificación de obra."}; dimensions: {"documented":[],"assumed":[{"label":"Altura de poste","value":8,"unit":"m"},{"label":"Vuelo de brazo","value":1.4,"unit":"m"}],"geometry":[]}; classification: {"layerId":"context_furniture","layerName":"Entorno · aparcamientos y luminarias","function":"Luminaria del entorno · ilustrativa 30"}; visualLayer: {"id":"context_furniture","name":"Entorno · aparcamientos y luminarias","defaultVisible":false}; representationKind: entorno_ilustrativo; quantityEligible: no; positioning: {"Sistema":"ETRS89 / UTM 29N · metros","Origen del modelo":"X 729400 · Y 4301550 · Z 285 m","Alcance":"Hasta 200 m desde el lindero del proyecto; solo exterior de parcela","Planta":"Distribución ilustrativa autorizada","Altimetría":"Plano ajustado a 213 puntos XYZ de aceras, extrapolado al resto del contexto; no es un MDT levantado"}; issues: ["Contexto para lectura del emplazamiento; planta derivada de cartografía, cotas y detalles simplificados. No para construcción ni mediciones de obra.","Las mediciones en el entorno expresan la geometría representada y conservan la precisión de su fuente."]; conceptual: {"enabled":true,"basis":"Distribución aproximada autorizada. No acredita la posición ni el número real de plazas o farolas existentes.","pending":["Posición real del mobiliario","Dimensiones y niveles definitivos"]}; geometryMetrics: {"boundingBoxM":{"min":[131.889756,-77.904812,1.860247],"max":[133.790685,-77.341822,9.970247]},"extentsM":[1.900929,0.56299,8.11],"meshSurfaceM2":5.532363,"meshVolumeM3":0.181319,"closedSolid":true,"basis":"Entorno de coordinación: trazados derivados de las fuentes indicadas por elemento; cotas, espesores, acabados y mobiliario orientativos cuando no están documentados. No acredita propiedad, servidumbres ni cantidades de obra y no es una base de construcción."}
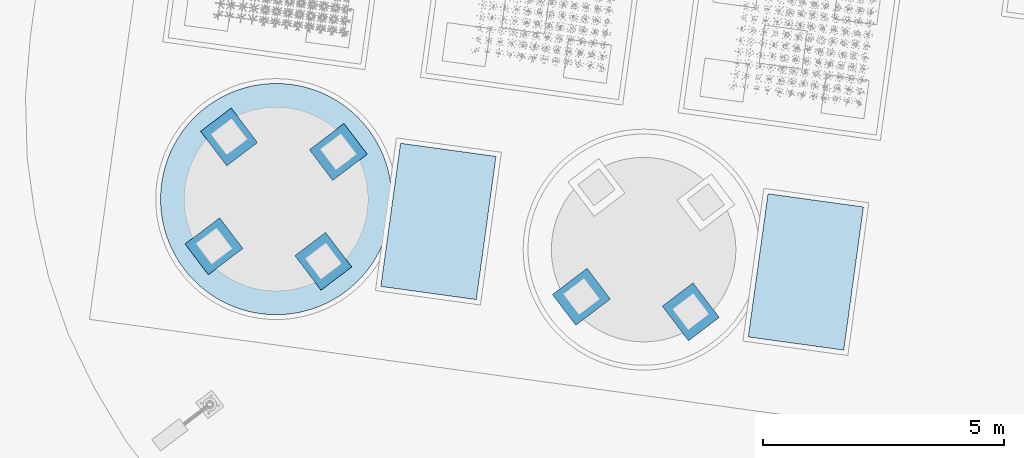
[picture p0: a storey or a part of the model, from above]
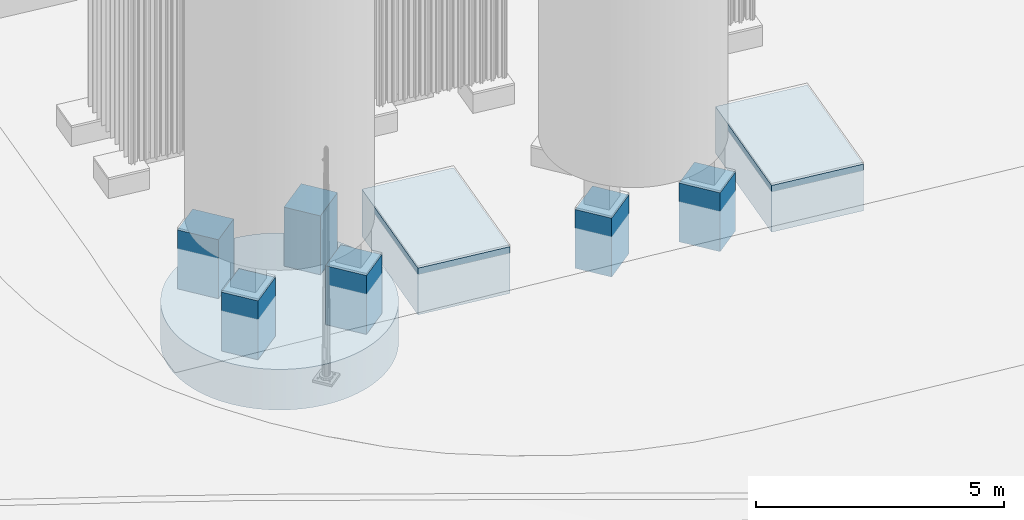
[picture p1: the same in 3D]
Properties of the parts of a building model (IFC4), part 93 of 134

# IfcLightFixture: Luminaria del entorno · ilustrativa 30
JH_Trazabilidad - Origen: Indicación del cliente · entorno de 200 m con aparcamientos y luminarias ilustrativos; Estado: provisional; Capa BIM: Entorno · aparcamientos y luminarias; Mediciones de obra: Excluido; Identificador: CTX-LIGHT-30; Categoria: Luminaria del entorno · ilustrativa 30; ClaseIFC: IfcLightFixture; EstadoDeInformacion: provisional; DocumentoFuente: {"documentId":"JH-CLIENT-CONTEXT-20260909","title":"Indicación del cliente · entorno de 200 m con aparcamientos y luminarias ilustrativos","date":"2026-09-09","note":"Distribución aproximada autorizada. No acredita la posición ni el número real de plazas o farolas existentes."}; IncidenciasPendientes: ["Contexto para lectura del emplazamiento; planta derivada de cartografía, cotas y detalles simplificados. No para construcción ni mediciones de obra.","Las mediciones en el entorno expresan la geometría representada y conservan la precisión de su fuente."]; UsoDeLasMagnitudes: Entorno de coordinación: trazados derivados de las fuentes indicadas por elemento; cotas, espesores, acabados y mobiliario orientativos cuando no están documentados. No acredita propiedad, servidumbres ni cantidades de obra y no es una base de construcción.
JH_CriterioDePosicion - PosicionYEstado: {"Sistema":"ETRS89 / UTM 29N · metros","Origen del modelo":"X 729400 · Y 4301550 · Z 285 m","Alcance":"Hasta 200 m desde el lindero del proyecto; solo exterior de parcela","Planta":"Distribución ilustrativa autorizada","Altimetría":"Plano ajustado a 213 puntos XYZ de aceras, extrapolado al resto del contexto; no es un MDT levantado"}
JH_EvidenciaDeMaterial - name: Luminaria exterior · gris; status: provisional; source: Acabado visual aproximado; no especificación de proyecto.
JH_CapaBIM - IdentificadorCapa: context_furniture; NombreCapa: Entorno · aparcamientos y luminarias; Funcion: Luminaria del entorno · ilustrativa 30; VisibilidadInicial: no
JH_EntornoContexto - Estado: provisional; Origen: {"documentId":"JH-CLIENT-CONTEXT-20260909","title":"Indicación del cliente · entorno de 200 m con aparcamientos y luminarias ilustrativos","date":"2026-09-09","note":"Distribución aproximada autorizada. No acredita la posición ni el número real de plazas o farolas existentes."}; Posicion: {"Sistema":"ETRS89 / UTM 29N · metros","Origen del modelo":"X 729400 · Y 4301550 · Z 285 m","Alcance":"Hasta 200 m desde el lindero del proyecto; solo exterior de parcela","Planta":"Distribución ilustrativa autorizada","Altimetría":"Plano ajustado a 213 puntos XYZ de aceras, extrapolado al resto del contexto; no es un MDT levantado"}; DimensionesSupuestas: [{"label":"Altura de poste","value":8,"unit":"m"},{"label":"Vuelo de brazo","value":1.4,"unit":"m"}]; IncluirEnMediciones: no; EsquemaIlustrativo: yes; Criterio: Entorno de coordinación: trazados derivados de las fuentes indicadas por elemento; cotas, espesores, acabados y mobiliario orientativos cuando no están documentados. No acredita propiedad, servidumbres ni cantidades de obra y no es una base de construcción.
JH_EsquemaProvisional - Estado: No para construcción; Origen: {"documentId":"JH-CLIENT-CONTEXT-20260909","title":"Indicación del cliente · entorno de 200 m con aparcamientos y luminarias ilustrativos","date":"2026-09-09","note":"Distribución aproximada autorizada. No acredita la posición ni el número real de plazas o farolas existentes."}; DimensionesSupuestas: [{"label":"Altura de poste","value":8,"unit":"m"},{"label":"Vuelo de brazo","value":1.4,"unit":"m"}]; Posicion: {"Sistema":"ETRS89 / UTM 29N · metros","Origen del modelo":"X 729400 · Y 4301550 · Z 285 m","Alcance":"Hasta 200 m desde el lindero del proyecto; solo exterior de parcela","Planta":"Distribución ilustrativa autorizada","Altimetría":"Plano ajustado a 213 puntos XYZ de aceras, extrapolado al resto del contexto; no es un MDT levantado"}; IncluirEnMediciones: no; Criterio: {"enabled":true,"basis":"Distribución aproximada autorizada. No acredita la posición ni el número real de plazas o farolas existentes.","pending":["Posición real del mobiliario","Dimensiones y niveles definitivos"]}

# IfcLightFixture: Luminaria del entorno · ilustrativa 31
In: Parcela industrial Jinhong
Description: Entorno de coordinación: trazados derivados de las fuentes indicadas por elemento; cotas, espesores, acabados y mobiliario orientativos cuando no están documentados. No acredita propiedad, servidumbres ni cantidades de obra y no es una base de construcción.; PredefinedType: USERDEFINED; Document: Indicación del cliente · entorno de 200 m con aparcamientos y luminarias ilustrativos; Entorno de Expacio Mérida · Catastro INSPIRE, PNOA y levantamiento Berrio; Levantamiento Berrio · parcelas I-27 Vial 3 e I-18 Vial 4; IGN · ortofotografía PNOA de máxima actualidad; Group: BIM · Entorno · aparcamientos y luminarias
JH_InformacionBIM - buildingId: context; buildingName: Entorno exterior de la parcela; level: Exterior · contexto de 200 m; category: Luminaria del entorno · ilustrativa 31; ifcClass: IfcLightFixture; status: provisional; source: {"documentId":"JH-CLIENT-CONTEXT-20260909","title":"Indicación del cliente · entorno de 200 m con aparcamientos y luminarias ilustrativos","date":"2026-09-09","note":"Distribución aproximada autorizada. No acredita la posición ni el número real de plazas o farolas existentes."}; material: {"name":"Luminaria exterior · gris","status":"provisional","source":"Acabado visual aproximado; no especificación de proyecto."}; appearance: {"profileId":"ctx_light","name":"Luminaria exterior · gris","status":"criterio_visual","basis":"Acabado de contexto orientativo, sin especificación de obra."}; dimensions: {"documented":[],"assumed":[{"label":"Altura de poste","value":8,"unit":"m"},{"label":"Vuelo de brazo","value":1.4,"unit":"m"}],"geometry":[]}; classification: {"layerId":"context_furniture","layerName":"Entorno · aparcamientos y luminarias","function":"Luminaria del entorno · ilustrativa 31"}; visualLayer: {"id":"context_furniture","name":"Entorno · aparcamientos y luminarias","defaultVisible":false}; representationKind: entorno_ilustrativo; quantityEligible: no; positioning: {"Sistema":"ETRS89 / UTM 29N · metros","Origen del modelo":"X 729400 · Y 4301550 · Z 285 m","Alcance":"Hasta 200 m desde el lindero del proyecto; solo exterior de parcela","Planta":"Distribución ilustrativa autorizada","Altimetría":"Plano ajustado a 213 puntos XYZ de aceras, extrapolado al resto del contexto; no es un MDT levantado"}; issues: ["Contexto para lectura del emplazamiento; planta derivada de cartografía, cotas y detalles simplificados. No para construcción ni mediciones de obra.","Las mediciones en el entorno expresan la geometría representada y conservan la precisión de su fuente."]; conceptual: {"enabled":true,"basis":"Distribución aproximada autorizada. No acredita la posición ni el número real de plazas o farolas existentes.","pending":["Posición real del mobiliario","Dimensiones y niveles definitivos"]}; geometryMetrics: {"boundingBoxM":{"min":[127.364273,-109.583196,1.724257],"max":[129.265202,-109.020206,9.834257]},"extentsM":[1.900929,0.56299,8.11],"meshSurfaceM2":5.532366,"meshVolumeM3":0.181319,"closedSolid":true,"basis":"Entorno de coordinación: trazados derivados de las fuentes indicadas por elemento; cotas, espesores, acabados y mobiliario orientativos cuando no están documentados. No acredita propiedad, servidumbres ni cantidades de obra y no es una base de construcción."}
JH_Trazabilidad - Origen: Indicación del cliente · entorno de 200 m con aparcamientos y luminarias ilustrativos; Estado: provisional; Capa BIM: Entorno · aparcamientos y luminarias; Mediciones de obra: Excluido; Identificador: CTX-LIGHT-31; Categoria: Luminaria del entorno · ilustrativa 31; ClaseIFC: IfcLightFixture; EstadoDeInformacion: provisional; DocumentoFuente: {"documentId":"JH-CLIENT-CONTEXT-20260909","title":"Indicación del cliente · entorno de 200 m con aparcamientos y luminarias ilustrativos","date":"2026-09-09","note":"Distribución aproximada autorizada. No acredita la posición ni el número real de plazas o farolas existentes."}; IncidenciasPendientes: ["Contexto para lectura del emplazamiento; planta derivada de cartografía, cotas y detalles simplificados. No para construcción ni mediciones de obra.","Las mediciones en el entorno expresan la geometría representada y conservan la precisión de su fuente."]; UsoDeLasMagnitudes: Entorno de coordinación: trazados derivados de las fuentes indicadas por elemento; cotas, espesores, acabados y mobiliario orientativos cuando no están documentados. No acredita propiedad, servidumbres ni cantidades de obra y no es una base de construcción.
JH_CriterioDePosicion - PosicionYEstado: {"Sistema":"ETRS89 / UTM 29N · metros","Origen del modelo":"X 729400 · Y 4301550 · Z 285 m","Alcance":"Hasta 200 m desde el lindero del proyecto; solo exterior de parcela","Planta":"Distribución ilustrativa autorizada","Altimetría":"Plano ajustado a 213 puntos XYZ de aceras, extrapolado al resto del contexto; no es un MDT levantado"}
JH_EvidenciaDeMaterial - name: Luminaria exterior · gris; status: provisional; source: Acabado visual aproximado; no especificación de proyecto.
JH_CapaBIM - IdentificadorCapa: context_furniture; NombreCapa: Entorno · aparcamientos y luminarias; Funcion: Luminaria del entorno · ilustrativa 31; VisibilidadInicial: no
JH_EntornoContexto - Estado: provisional; Origen: {"documentId":"JH-CLIENT-CONTEXT-20260909","title":"Indicación del cliente · entorno de 200 m con aparcamientos y luminarias ilustrativos","date":"2026-09-09","note":"Distribución aproximada autorizada. No acredita la posición ni el número real de plazas o farolas existentes."}; Posicion: {"Sistema":"ETRS89 / UTM 29N · metros","Origen del modelo":"X 729400 · Y 4301550 · Z 285 m","Alcance":"Hasta 200 m desde el lindero del proyecto; solo exterior de parcela","Planta":"Distribución ilustrativa autorizada","Altimetría":"Plano ajustado a 213 puntos XYZ de aceras, extrapolado al resto del contexto; no es un MDT levantado"}; DimensionesSupuestas: [{"label":"Altura de poste","value":8,"unit":"m"},{"label":"Vuelo de brazo","value":1.4,"unit":"m"}]; IncluirEnMediciones: no; EsquemaIlustrativo: yes; Criterio: Entorno de coordinación: trazados derivados de las fuentes indicadas por elemento; cotas, espesores, acabados y mobiliario orientativos cuando no están documentados. No acredita propiedad, servidumbres ni cantidades de obra y no es una base de construcción.
JH_EsquemaProvisional - Estado: No para construcción; Origen: {"documentId":"JH-CLIENT-CONTEXT-20260909","title":"Indicación del cliente · entorno de 200 m con aparcamientos y luminarias ilustrativos","date":"2026-09-09","note":"Distribución aproximada autorizada. No acredita la posición ni el número real de plazas o farolas existentes."}; DimensionesSupuestas: [{"label":"Altura de poste","value":8,"unit":"m"},{"label":"Vuelo de brazo","value":1.4,"unit":"m"}]; Posicion: {"Sistema":"ETRS89 / UTM 29N · metros","Origen del modelo":"X 729400 · Y 4301550 · Z 285 m","Alcance":"Hasta 200 m desde el lindero del proyecto; solo exterior de parcela","Planta":"Distribución ilustrativa autorizada","Altimetría":"Plano ajustado a 213 puntos XYZ de aceras, extrapolado al resto del contexto; no es un MDT levantado"}; IncluirEnMediciones: no; Criterio: {"enabled":true,"basis":"Distribución aproximada autorizada. No acredita la posición ni el número real de plazas o farolas existentes.","pending":["Posición real del mobiliario","Dimensiones y niveles definitivos"]}

# IfcLightFixture: Luminaria del entorno · ilustrativa 32
In: Parcela industrial Jinhong
Description: Entorno de coordinación: trazados derivados de las fuentes indicadas por elemento; cotas, espesores, acabados y mobiliario orientativos cuando no están documentados. No acredita propiedad, servidumbres ni cantidades de obra y no es una base de construcción.; PredefinedType: USERDEFINED; Document: Indicación del cliente · entorno de 200 m con aparcamientos y luminarias ilustrativos; Entorno de Expacio Mérida · Catastro INSPIRE, PNOA y levantamiento Berrio; Levantamiento Berrio · parcelas I-27 Vial 3 e I-18 Vial 4; IGN · ortofotografía PNOA de máxima actualidad; Group: BIM · Entorno · aparcamientos y luminarias
JH_InformacionBIM - buildingId: context; buildingName: Entorno exterior de la parcela; level: Exterior · contexto de 200 m; category: Luminaria del entorno · ilustrativa 32; ifcClass: IfcLightFixture; status: provisional; source: {"documentId":"JH-CLIENT-CONTEXT-20260909","title":"Indicación del cliente · entorno de 200 m con aparcamientos y luminarias ilustrativos","date":"2026-09-09","note":"Distribución aproximada autorizada. No acredita la posición ni el número real de plazas o farolas existentes."}; material: {"name":"Luminaria exterior · gris","status":"provisional","source":"Acabado visual aproximado; no especificación de proyecto."}; appearance: {"profileId":"ctx_light","name":"Luminaria exterior · gris","status":"criterio_visual","basis":"Acabado de contexto orientativo, sin especificación de obra."}; dimensions: {"documented":[],"assumed":[{"label":"Altura de poste","value":8,"unit":"m"},{"label":"Vuelo de brazo","value":1.4,"unit":"m"}],"geometry":[]}; classification: {"layerId":"context_furniture","layerName":"Entorno · aparcamientos y luminarias","function":"Luminaria del entorno · ilustrativa 32"}; visualLayer: {"id":"context_furniture","name":"Entorno · aparcamientos y luminarias","defaultVisible":false}; representationKind: entorno_ilustrativo; quantityEligible: no; positioning: {"Sistema":"ETRS89 / UTM 29N · metros","Origen del modelo":"X 729400 · Y 4301550 · Z 285 m","Alcance":"Hasta 200 m desde el lindero del proyecto; solo exterior de parcela","Planta":"Distribución ilustrativa autorizada","Altimetría":"Plano ajustado a 213 puntos XYZ de aceras, extrapolado al resto del contexto; no es un MDT levantado"}; issues: ["Contexto para lectura del emplazamiento; planta derivada de cartografía, cotas y detalles simplificados. No para construcción ni mediciones de obra.","Las mediciones en el entorno expresan la geometría representada y conservan la precisión de su fuente."]; conceptual: {"enabled":true,"basis":"Distribución aproximada autorizada. No acredita la posición ni el número real de plazas o farolas existentes.","pending":["Posición real del mobiliario","Dimensiones y niveles definitivos"]}; geometryMetrics: {"boundingBoxM":{"min":[123.333764,-141.332291,1.593708],"max":[125.234693,-140.769301,9.703708]},"extentsM":[1.900929,0.56299,8.11],"meshSurfaceM2":5.532363,"meshVolumeM3":0.181319,"closedSolid":true,"basis":"Entorno de coordinación: trazados derivados de las fuentes indicadas por elemento; cotas, espesores, acabados y mobiliario orientativos cuando no están documentados. No acredita propiedad, servidumbres ni cantidades de obra y no es una base de construcción."}
JH_Trazabilidad - Origen: Indicación del cliente · entorno de 200 m con aparcamientos y luminarias ilustrativos; Estado: provisional; Capa BIM: Entorno · aparcamientos y luminarias; Mediciones de obra: Excluido; Identificador: CTX-LIGHT-32; Categoria: Luminaria del entorno · ilustrativa 32; ClaseIFC: IfcLightFixture; EstadoDeInformacion: provisional; DocumentoFuente: {"documentId":"JH-CLIENT-CONTEXT-20260909","title":"Indicación del cliente · entorno de 200 m con aparcamientos y luminarias ilustrativos","date":"2026-09-09","note":"Distribución aproximada autorizada. No acredita la posición ni el número real de plazas o farolas existentes."}; IncidenciasPendientes: ["Contexto para lectura del emplazamiento; planta derivada de cartografía, cotas y detalles simplificados. No para construcción ni mediciones de obra.","Las mediciones en el entorno expresan la geometría representada y conservan la precisión de su fuente."]; UsoDeLasMagnitudes: Entorno de coordinación: trazados derivados de las fuentes indicadas por elemento; cotas, espesores, acabados y mobiliario orientativos cuando no están documentados. No acredita propiedad, servidumbres ni cantidades de obra y no es una base de construcción.
JH_CriterioDePosicion - PosicionYEstado: {"Sistema":"ETRS89 / UTM 29N · metros","Origen del modelo":"X 729400 · Y 4301550 · Z 285 m","Alcance":"Hasta 200 m desde el lindero del proyecto; solo exterior de parcela","Planta":"Distribución ilustrativa autorizada","Altimetría":"Plano ajustado a 213 puntos XYZ de aceras, extrapolado al resto del contexto; no es un MDT levantado"}
JH_EvidenciaDeMaterial - name: Luminaria exterior · gris; status: provisional; source: Acabado visual aproximado; no especificación de proyecto.
JH_CapaBIM - IdentificadorCapa: context_furniture; NombreCapa: Entorno · aparcamientos y luminarias; Funcion: Luminaria del entorno · ilustrativa 32; VisibilidadInicial: no
JH_EntornoContexto - Estado: provisional; Origen: {"documentId":"JH-CLIENT-CONTEXT-20260909","title":"Indicación del cliente · entorno de 200 m con aparcamientos y luminarias ilustrativos","date":"2026-09-09","note":"Distribución aproximada autorizada. No acredita la posición ni el número real de plazas o farolas existentes."}; Posicion: {"Sistema":"ETRS89 / UTM 29N · metros","Origen del modelo":"X 729400 · Y 4301550 · Z 285 m","Alcance":"Hasta 200 m desde el lindero del proyecto; solo exterior de parcela","Planta":"Distribución ilustrativa autorizada","Altimetría":"Plano ajustado a 213 puntos XYZ de aceras, extrapolado al resto del contexto; no es un MDT levantado"}; DimensionesSupuestas: [{"label":"Altura de poste","value":8,"unit":"m"},{"label":"Vuelo de brazo","value":1.4,"unit":"m"}]; IncluirEnMediciones: no; EsquemaIlustrativo: yes; Criterio: Entorno de coordinación: trazados derivados de las fuentes indicadas por elemento; cotas, espesores, acabados y mobiliario orientativos cuando no están documentados. No acredita propiedad, servidumbres ni cantidades de obra y no es una base de construcción.
JH_EsquemaProvisional - Estado: No para construcción; Origen: {"documentId":"JH-CLIENT-CONTEXT-20260909","title":"Indicación del cliente · entorno de 200 m con aparcamientos y luminarias ilustrativos","date":"2026-09-09","note":"Distribución aproximada autorizada. No acredita la posición ni el número real de plazas o farolas existentes."}; DimensionesSupuestas: [{"label":"Altura de poste","value":8,"unit":"m"},{"label":"Vuelo de brazo","value":1.4,"unit":"m"}]; Posicion: {"Sistema":"ETRS89 / UTM 29N · metros","Origen del modelo":"X 729400 · Y 4301550 · Z 285 m","Alcance":"Hasta 200 m desde el lindero del proyecto; solo exterior de parcela","Planta":"Distribución ilustrativa autorizada","Altimetría":"Plano ajustado a 213 puntos XYZ de aceras, extrapolado al resto del contexto; no es un MDT levantado"}; IncluirEnMediciones: no; Criterio: {"enabled":true,"basis":"Distribución aproximada autorizada. No acredita la posición ni el número real de plazas o farolas existentes.","pending":["Posición real del mobiliario","Dimensiones y niveles definitivos"]}

# IfcLightFixture: Luminaria del entorno · ilustrativa 33
In: Parcela industrial Jinhong
Description: Entorno de coordinación: trazados derivados de las fuentes indicadas por elemento; cotas, espesores, acabados y mobiliario orientativos cuando no están documentados. No acredita propiedad, servidumbres ni cantidades de obra y no es una base de construcción.; PredefinedType: USERDEFINED; Document: Indicación del cliente · entorno de 200 m con aparcamientos y luminarias ilustrativos; Entorno de Expacio Mérida · Catastro INSPIRE, PNOA y levantamiento Berrio; Levantamiento Berrio · parcelas I-27 Vial 3 e I-18 Vial 4; IGN · ortofotografía PNOA de máxima actualidad; Group: BIM · Entorno · aparcamientos y luminarias
JH_InformacionBIM - buildingId: context; buildingName: Entorno exterior de la parcela; level: Exterior · contexto de 200 m; category: Luminaria del entorno · ilustrativa 33; ifcClass: IfcLightFixture; status: provisional; source: {"documentId":"JH-CLIENT-CONTEXT-20260909","title":"Indicación del cliente · entorno de 200 m con aparcamientos y luminarias ilustrativos","date":"2026-09-09","note":"Distribución aproximada autorizada. No acredita la posición ni el número real de plazas o farolas existentes."}; material: {"name":"Luminaria exterior · gris","status":"provisional","source":"Acabado visual aproximado; no especificación de proyecto."}; appearance: {"profileId":"ctx_light","name":"Luminaria exterior · gris","status":"criterio_visual","basis":"Acabado de contexto orientativo, sin especificación de obra."}; dimensions: {"documented":[],"assumed":[{"label":"Altura de poste","value":8,"unit":"m"},{"label":"Vuelo de brazo","value":1.4,"unit":"m"}],"geometry":[]}; classification: {"layerId":"context_furniture","layerName":"Entorno · aparcamientos y luminarias","function":"Luminaria del entorno · ilustrativa 33"}; visualLayer: {"id":"context_furniture","name":"Entorno · aparcamientos y luminarias","defaultVisible":false}; representationKind: entorno_ilustrativo; quantityEligible: no; positioning: {"Sistema":"ETRS89 / UTM 29N · metros","Origen del modelo":"X 729400 · Y 4301550 · Z 285 m","Alcance":"Hasta 200 m desde el lindero del proyecto; solo exterior de parcela","Planta":"Distribución ilustrativa autorizada","Altimetría":"Plano ajustado a 213 puntos XYZ de aceras, extrapolado al resto del contexto; no es un MDT levantado"}; issues: ["Contexto para lectura del emplazamiento; planta derivada de cartografía, cotas y detalles simplificados. No para construcción ni mediciones de obra.","Las mediciones en el entorno expresan la geometría representada y conservan la precisión de su fuente."]; conceptual: {"enabled":true,"basis":"Distribución aproximada autorizada. No acredita la posición ni el número real de plazas o farolas existentes.","pending":["Posición real del mobiliario","Dimensiones y niveles definitivos"]}; geometryMetrics: {"boundingBoxM":{"min":[118.808281,-173.010674,1.457719],"max":[120.70921,-172.447685,9.567719]},"extentsM":[1.900929,0.562989,8.11],"meshSurfaceM2":5.532366,"meshVolumeM3":0.181319,"closedSolid":true,"basis":"Entorno de coordinación: trazados derivados de las fuentes indicadas por elemento; cotas, espesores, acabados y mobiliario orientativos cuando no están documentados. No acredita propiedad, servidumbres ni cantidades de obra y no es una base de construcción."}
JH_Trazabilidad - Origen: Indicación del cliente · entorno de 200 m con aparcamientos y luminarias ilustrativos; Estado: provisional; Capa BIM: Entorno · aparcamientos y luminarias; Mediciones de obra: Excluido; Identificador: CTX-LIGHT-33; Categoria: Luminaria del entorno · ilustrativa 33; ClaseIFC: IfcLightFixture; EstadoDeInformacion: provisional; DocumentoFuente: {"documentId":"JH-CLIENT-CONTEXT-20260909","title":"Indicación del cliente · entorno de 200 m con aparcamientos y luminarias ilustrativos","date":"2026-09-09","note":"Distribución aproximada autorizada. No acredita la posición ni el número real de plazas o farolas existentes."}; IncidenciasPendientes: ["Contexto para lectura del emplazamiento; planta derivada de cartografía, cotas y detalles simplificados. No para construcción ni mediciones de obra.","Las mediciones en el entorno expresan la geometría representada y conservan la precisión de su fuente."]; UsoDeLasMagnitudes: Entorno de coordinación: trazados derivados de las fuentes indicadas por elemento; cotas, espesores, acabados y mobiliario orientativos cuando no están documentados. No acredita propiedad, servidumbres ni cantidades de obra y no es una base de construcción.
JH_CriterioDePosicion - PosicionYEstado: {"Sistema":"ETRS89 / UTM 29N · metros","Origen del modelo":"X 729400 · Y 4301550 · Z 285 m","Alcance":"Hasta 200 m desde el lindero del proyecto; solo exterior de parcela","Planta":"Distribución ilustrativa autorizada","Altimetría":"Plano ajustado a 213 puntos XYZ de aceras, extrapolado al resto del contexto; no es un MDT levantado"}
JH_EvidenciaDeMaterial - name: Luminaria exterior · gris; status: provisional; source: Acabado visual aproximado; no especificación de proyecto.
JH_CapaBIM - IdentificadorCapa: context_furniture; NombreCapa: Entorno · aparcamientos y luminarias; Funcion: Luminaria del entorno · ilustrativa 33; VisibilidadInicial: no
JH_EntornoContexto - Estado: provisional; Origen: {"documentId":"JH-CLIENT-CONTEXT-20260909","title":"Indicación del cliente · entorno de 200 m con aparcamientos y luminarias ilustrativos","date":"2026-09-09","note":"Distribución aproximada autorizada. No acredita la posición ni el número real de plazas o farolas existentes."}; Posicion: {"Sistema":"ETRS89 / UTM 29N · metros","Origen del modelo":"X 729400 · Y 4301550 · Z 285 m","Alcance":"Hasta 200 m desde el lindero del proyecto; solo exterior de parcela","Planta":"Distribución ilustrativa autorizada","Altimetría":"Plano ajustado a 213 puntos XYZ de aceras, extrapolado al resto del contexto; no es un MDT levantado"}; DimensionesSupuestas: [{"label":"Altura de poste","value":8,"unit":"m"},{"label":"Vuelo de brazo","value":1.4,"unit":"m"}]; IncluirEnMediciones: no; EsquemaIlustrativo: yes; Criterio: Entorno de coordinación: trazados derivados de las fuentes indicadas por elemento; cotas, espesores, acabados y mobiliario orientativos cuando no están documentados. No acredita propiedad, servidumbres ni cantidades de obra y no es una base de construcción.
JH_EsquemaProvisional - Estado: No para construcción; Origen: {"documentId":"JH-CLIENT-CONTEXT-20260909","title":"Indicación del cliente · entorno de 200 m con aparcamientos y luminarias ilustrativos","date":"2026-09-09","note":"Distribución aproximada autorizada. No acredita la posición ni el número real de plazas o farolas existentes."}; DimensionesSupuestas: [{"label":"Altura de poste","value":8,"unit":"m"},{"label":"Vuelo de brazo","value":1.4,"unit":"m"}]; Posicion: {"Sistema":"ETRS89 / UTM 29N · metros","Origen del modelo":"X 729400 · Y 4301550 · Z 285 m","Alcance":"Hasta 200 m desde el lindero del proyecto; solo exterior de parcela","Planta":"Distribución ilustrativa autorizada","Altimetría":"Plano ajustado a 213 puntos XYZ de aceras, extrapolado al resto del contexto; no es un MDT levantado"}; IncluirEnMediciones: no; Criterio: {"enabled":true,"basis":"Distribución aproximada autorizada. No acredita la posición ni el número real de plazas o farolas existentes.","pending":["Posición real del mobiliario","Dimensiones y niveles definitivos"]}

# IfcLightFixture: Luminaria del entorno · ilustrativa 34
In: Parcela industrial Jinhong
Description: Entorno de coordinación: trazados derivados de las fuentes indicadas por elemento; cotas, espesores, acabados y mobiliario orientativos cuando no están documentados. No acredita propiedad, servidumbres ni cantidades de obra y no es una base de construcción.; PredefinedType: USERDEFINED; Document: Indicación del cliente · entorno de 200 m con aparcamientos y luminarias ilustrativos; Entorno de Expacio Mérida · Catastro INSPIRE, PNOA y levantamiento Berrio; Levantamiento Berrio · parcelas I-27 Vial 3 e I-18 Vial 4; IGN · ortofotografía PNOA de máxima actualidad; Group: BIM · Entorno · aparcamientos y luminarias
JH_InformacionBIM - buildingId: context; buildingName: Entorno exterior de la parcela; level: Exterior · contexto de 200 m; category: Luminaria del entorno · ilustrativa 34; ifcClass: IfcLightFixture; status: provisional; source: {"documentId":"JH-CLIENT-CONTEXT-20260909","title":"Indicación del cliente · entorno de 200 m con aparcamientos y luminarias ilustrativos","date":"2026-09-09","note":"Distribución aproximada autorizada. No acredita la posición ni el número real de plazas o farolas existentes."}; material: {"name":"Luminaria exterior · gris","status":"provisional","source":"Acabado visual aproximado; no especificación de proyecto."}; appearance: {"profileId":"ctx_light","name":"Luminaria exterior · gris","status":"criterio_visual","basis":"Acabado de contexto orientativo, sin especificación de obra."}; dimensions: {"documented":[],"assumed":[{"label":"Altura de poste","value":8,"unit":"m"},{"label":"Vuelo de brazo","value":1.4,"unit":"m"}],"geometry":[]}; classification: {"layerId":"context_furniture","layerName":"Entorno · aparcamientos y luminarias","function":"Luminaria del entorno · ilustrativa 34"}; visualLayer: {"id":"context_furniture","name":"Entorno · aparcamientos y luminarias","defaultVisible":false}; representationKind: entorno_ilustrativo; quantityEligible: no; positioning: {"Sistema":"ETRS89 / UTM 29N · metros","Origen del modelo":"X 729400 · Y 4301550 · Z 285 m","Alcance":"Hasta 200 m desde el lindero del proyecto; solo exterior de parcela","Planta":"Distribución ilustrativa autorizada","Altimetría":"Plano ajustado a 213 puntos XYZ de aceras, extrapolado al resto del contexto; no es un MDT levantado"}; issues: ["Contexto para lectura del emplazamiento; planta derivada de cartografía, cotas y detalles simplificados. No para construcción ni mediciones de obra.","Las mediciones en el entorno expresan la geometría representada y conservan la precisión de su fuente."]; conceptual: {"enabled":true,"basis":"Distribución aproximada autorizada. No acredita la posición ni el número real de plazas o farolas existentes.","pending":["Posición real del mobiliario","Dimensiones y niveles definitivos"]}; geometryMetrics: {"boundingBoxM":{"min":[261.162842,-65.652754,3.346663],"max":[263.070894,-65.148448,11.456663]},"extentsM":[1.908052,0.504306,8.11],"meshSurfaceM2":5.532365,"meshVolumeM3":0.181319,"closedSolid":true,"basis":"Entorno de coordinación: trazados derivados de las fuentes indicadas por elemento; cotas, espesores, acabados y mobiliario orientativos cuando no están documentados. No acredita propiedad, servidumbres ni cantidades de obra y no es una base de construcción."}
JH_Trazabilidad - Origen: Indicación del cliente · entorno de 200 m con aparcamientos y luminarias ilustrativos; Estado: provisional; Capa BIM: Entorno · aparcamientos y luminarias; Mediciones de obra: Excluido; Identificador: CTX-LIGHT-34; Categoria: Luminaria del entorno · ilustrativa 34; ClaseIFC: IfcLightFixture; EstadoDeInformacion: provisional; DocumentoFuente: {"documentId":"JH-CLIENT-CONTEXT-20260909","title":"Indicación del cliente · entorno de 200 m con aparcamientos y luminarias ilustrativos","date":"2026-09-09","note":"Distribución aproximada autorizada. No acredita la posición ni el número real de plazas o farolas existentes."}; IncidenciasPendientes: ["Contexto para lectura del emplazamiento; planta derivada de cartografía, cotas y detalles simplificados. No para construcción ni mediciones de obra.","Las mediciones en el entorno expresan la geometría representada y conservan la precisión de su fuente."]; UsoDeLasMagnitudes: Entorno de coordinación: trazados derivados de las fuentes indicadas por elemento; cotas, espesores, acabados y mobiliario orientativos cuando no están documentados. No acredita propiedad, servidumbres ni cantidades de obra y no es una base de construcción.
JH_CriterioDePosicion - PosicionYEstado: {"Sistema":"ETRS89 / UTM 29N · metros","Origen del modelo":"X 729400 · Y 4301550 · Z 285 m","Alcance":"Hasta 200 m desde el lindero del proyecto; solo exterior de parcela","Planta":"Distribución ilustrativa autorizada","Altimetría":"Plano ajustado a 213 puntos XYZ de aceras, extrapolado al resto del contexto; no es un MDT levantado"}
JH_EvidenciaDeMaterial - name: Luminaria exterior · gris; status: provisional; source: Acabado visual aproximado; no especificación de proyecto.
JH_CapaBIM - IdentificadorCapa: context_furniture; NombreCapa: Entorno · aparcamientos y luminarias; Funcion: Luminaria del entorno · ilustrativa 34; VisibilidadInicial: no
JH_EntornoContexto - Estado: provisional; Origen: {"documentId":"JH-CLIENT-CONTEXT-20260909","title":"Indicación del cliente · entorno de 200 m con aparcamientos y luminarias ilustrativos","date":"2026-09-09","note":"Distribución aproximada autorizada. No acredita la posición ni el número real de plazas o farolas existentes."}; Posicion: {"Sistema":"ETRS89 / UTM 29N · metros","Origen del modelo":"X 729400 · Y 4301550 · Z 285 m","Alcance":"Hasta 200 m desde el lindero del proyecto; solo exterior de parcela","Planta":"Distribución ilustrativa autorizada","Altimetría":"Plano ajustado a 213 puntos XYZ de aceras, extrapolado al resto del contexto; no es un MDT levantado"}; DimensionesSupuestas: [{"label":"Altura de poste","value":8,"unit":"m"},{"label":"Vuelo de brazo","value":1.4,"unit":"m"}]; IncluirEnMediciones: no; EsquemaIlustrativo: yes; Criterio: Entorno de coordinación: trazados derivados de las fuentes indicadas por elemento; cotas, espesores, acabados y mobiliario orientativos cuando no están documentados. No acredita propiedad, servidumbres ni cantidades de obra y no es una base de construcción.
JH_EsquemaProvisional - Estado: No para construcción; Origen: {"documentId":"JH-CLIENT-CONTEXT-20260909","title":"Indicación del cliente · entorno de 200 m con aparcamientos y luminarias ilustrativos","date":"2026-09-09","note":"Distribución aproximada autorizada. No acredita la posición ni el número real de plazas o farolas existentes."}; DimensionesSupuestas: [{"label":"Altura de poste","value":8,"unit":"m"},{"label":"Vuelo de brazo","value":1.4,"unit":"m"}]; Posicion: {"Sistema":"ETRS89 / UTM 29N · metros","Origen del modelo":"X 729400 · Y 4301550 · Z 285 m","Alcance":"Hasta 200 m desde el lindero del proyecto; solo exterior de parcela","Planta":"Distribución ilustrativa autorizada","Altimetría":"Plano ajustado a 213 puntos XYZ de aceras, extrapolado al resto del contexto; no es un MDT levantado"}; IncluirEnMediciones: no; Criterio: {"enabled":true,"basis":"Distribución aproximada autorizada. No acredita la posición ni el número real de plazas o farolas existentes.","pending":["Posición real del mobiliario","Dimensiones y niveles definitivos"]}

# IfcLightFixture: Luminaria del entorno · ilustrativa 35
In: Parcela industrial Jinhong
Description: Entorno de coordinación: trazados derivados de las fuentes indicadas por elemento; cotas, espesores, acabados y mobiliario orientativos cuando no están documentados. No acredita propiedad, servidumbres ni cantidades de obra y no es una base de construcción.; PredefinedType: USERDEFINED; Document: Indicación del cliente · entorno de 200 m con aparcamientos y luminarias ilustrativos; Entorno de Expacio Mérida · Catastro INSPIRE, PNOA y levantamiento Berrio; Levantamiento Berrio · parcelas I-27 Vial 3 e I-18 Vial 4; IGN · ortofotografía PNOA de máxima actualidad; Group: BIM · Entorno · aparcamientos y luminarias
JH_InformacionBIM - buildingId: context; buildingName: Entorno exterior de la parcela; level: Exterior · contexto de 200 m; category: Luminaria del entorno · ilustrativa 35; ifcClass: IfcLightFixture; status: provisional; source: {"documentId":"JH-CLIENT-CONTEXT-20260909","title":"Indicación del cliente · entorno de 200 m con aparcamientos y luminarias ilustrativos","date":"2026-09-09","note":"Distribución aproximada autorizada. No acredita la posición ni el número real de plazas o farolas existentes."}; material: {"name":"Luminaria exterior · gris","status":"provisional","source":"Acabado visual aproximado; no especificación de proyecto."}; appearance: {"profileId":"ctx_light","name":"Luminaria exterior · gris","status":"criterio_visual","basis":"Acabado de contexto orientativo, sin especificación de obra."}; dimensions: {"documented":[],"assumed":[{"label":"Altura de poste","value":8,"unit":"m"},{"label":"Vuelo de brazo","value":1.4,"unit":"m"}],"geometry":[]}; classification: {"layerId":"context_furniture","layerName":"Entorno · aparcamientos y luminarias","function":"Luminaria del entorno · ilustrativa 35"}; visualLayer: {"id":"context_furniture","name":"Entorno · aparcamientos y luminarias","defaultVisible":false}; representationKind: entorno_ilustrativo; quantityEligible: no; positioning: {"Sistema":"ETRS89 / UTM 29N · metros","Origen del modelo":"X 729400 · Y 4301550 · Z 285 m","Alcance":"Hasta 200 m desde el lindero del proyecto; solo exterior de parcela","Planta":"Distribución ilustrativa autorizada","Altimetría":"Plano ajustado a 213 puntos XYZ de aceras, extrapolado al resto del contexto; no es un MDT levantado"}; issues: ["Contexto para lectura del emplazamiento; planta derivada de cartografía, cotas y detalles simplificados. No para construcción ni mediciones de obra.","Las mediciones en el entorno expresan la geometría representada y conservan la precisión de su fuente."]; conceptual: {"enabled":true,"basis":"Distribución aproximada autorizada. No acredita la posición ni el número real de plazas o farolas existentes.","pending":["Posición real del mobiliario","Dimensiones y niveles definitivos"]}; geometryMetrics: {"boundingBoxM":{"min":[257.978723,-97.493944,3.225493],"max":[259.886775,-96.989638,11.335493]},"extentsM":[1.908052,0.504306,8.11],"meshSurfaceM2":5.532365,"meshVolumeM3":0.181319,"closedSolid":true,"basis":"Entorno de coordinación: trazados derivados de las fuentes indicadas por elemento; cotas, espesores, acabados y mobiliario orientativos cuando no están documentados. No acredita propiedad, servidumbres ni cantidades de obra y no es una base de construcción."}
JH_Trazabilidad - Origen: Indicación del cliente · entorno de 200 m con aparcamientos y luminarias ilustrativos; Estado: provisional; Capa BIM: Entorno · aparcamientos y luminarias; Mediciones de obra: Excluido; Identificador: CTX-LIGHT-35; Categoria: Luminaria del entorno · ilustrativa 35; ClaseIFC: IfcLightFixture; EstadoDeInformacion: provisional; DocumentoFuente: {"documentId":"JH-CLIENT-CONTEXT-20260909","title":"Indicación del cliente · entorno de 200 m con aparcamientos y luminarias ilustrativos","date":"2026-09-09","note":"Distribución aproximada autorizada. No acredita la posición ni el número real de plazas o farolas existentes."}; IncidenciasPendientes: ["Contexto para lectura del emplazamiento; planta derivada de cartografía, cotas y detalles simplificados. No para construcción ni mediciones de obra.","Las mediciones en el entorno expresan la geometría representada y conservan la precisión de su fuente."]; UsoDeLasMagnitudes: Entorno de coordinación: trazados derivados de las fuentes indicadas por elemento; cotas, espesores, acabados y mobiliario orientativos cuando no están documentados. No acredita propiedad, servidumbres ni cantidades de obra y no es una base de construcción.
JH_CriterioDePosicion - PosicionYEstado: {"Sistema":"ETRS89 / UTM 29N · metros","Origen del modelo":"X 729400 · Y 4301550 · Z 285 m","Alcance":"Hasta 200 m desde el lindero del proyecto; solo exterior de parcela","Planta":"Distribución ilustrativa autorizada","Altimetría":"Plano ajustado a 213 puntos XYZ de aceras, extrapolado al resto del contexto; no es un MDT levantado"}
JH_EvidenciaDeMaterial - name: Luminaria exterior · gris; status: provisional; source: Acabado visual aproximado; no especificación de proyecto.
JH_CapaBIM - IdentificadorCapa: context_furniture; NombreCapa: Entorno · aparcamientos y luminarias; Funcion: Luminaria del entorno · ilustrativa 35; VisibilidadInicial: no
JH_EntornoContexto - Estado: provisional; Origen: {"documentId":"JH-CLIENT-CONTEXT-20260909","title":"Indicación del cliente · entorno de 200 m con aparcamientos y luminarias ilustrativos","date":"2026-09-09","note":"Distribución aproximada autorizada. No acredita la posición ni el número real de plazas o farolas existentes."}; Posicion: {"Sistema":"ETRS89 / UTM 29N · metros","Origen del modelo":"X 729400 · Y 4301550 · Z 285 m","Alcance":"Hasta 200 m desde el lindero del proyecto; solo exterior de parcela","Planta":"Distribución ilustrativa autorizada","Altimetría":"Plano ajustado a 213 puntos XYZ de aceras, extrapolado al resto del contexto; no es un MDT levantado"}; DimensionesSupuestas: [{"label":"Altura de poste","value":8,"unit":"m"},{"label":"Vuelo de brazo","value":1.4,"unit":"m"}]; IncluirEnMediciones: no; EsquemaIlustrativo: yes; Criterio: Entorno de coordinación: trazados derivados de las fuentes indicadas por elemento; cotas, espesores, acabados y mobiliario orientativos cuando no están documentados. No acredita propiedad, servidumbres ni cantidades de obra y no es una base de construcción.
JH_EsquemaProvisional - Estado: No para construcción; Origen: {"documentId":"JH-CLIENT-CONTEXT-20260909","title":"Indicación del cliente · entorno de 200 m con aparcamientos y luminarias ilustrativos","date":"2026-09-09","note":"Distribución aproximada autorizada. No acredita la posición ni el número real de plazas o farolas existentes."}; DimensionesSupuestas: [{"label":"Altura de poste","value":8,"unit":"m"},{"label":"Vuelo de brazo","value":1.4,"unit":"m"}]; Posicion: {"Sistema":"ETRS89 / UTM 29N · metros","Origen del modelo":"X 729400 · Y 4301550 · Z 285 m","Alcance":"Hasta 200 m desde el lindero del proyecto; solo exterior de parcela","Planta":"Distribución ilustrativa autorizada","Altimetría":"Plano ajustado a 213 puntos XYZ de aceras, extrapolado al resto del contexto; no es un MDT levantado"}; IncluirEnMediciones: no; Criterio: {"enabled":true,"basis":"Distribución aproximada autorizada. No acredita la posición ni el número real de plazas o farolas existentes.","pending":["Posición real del mobiliario","Dimensiones y niveles definitivos"]}

# IfcLightFixture: Luminaria del entorno · ilustrativa 36
In: Parcela industrial Jinhong
Description: Entorno de coordinación: trazados derivados de las fuentes indicadas por elemento; cotas, espesores, acabados y mobiliario orientativos cuando no están documentados. No acredita propiedad, servidumbres ni cantidades de obra y no es una base de construcción.; PredefinedType: USERDEFINED; Document: Indicación del cliente · entorno de 200 m con aparcamientos y luminarias ilustrativos; Entorno de Expacio Mérida · Catastro INSPIRE, PNOA y levantamiento Berrio; Levantamiento Berrio · parcelas I-27 Vial 3 e I-18 Vial 4; IGN · ortofotografía PNOA de máxima actualidad; Group: BIM · Entorno · aparcamientos y luminarias
JH_InformacionBIM - buildingId: context; buildingName: Entorno exterior de la parcela; level: Exterior · contexto de 200 m; category: Luminaria del entorno · ilustrativa 36; ifcClass: IfcLightFixture; status: provisional; source: {"documentId":"JH-CLIENT-CONTEXT-20260909","title":"Indicación del cliente · entorno de 200 m con aparcamientos y luminarias ilustrativos","date":"2026-09-09","note":"Distribución aproximada autorizada. No acredita la posición ni el número real de plazas o farolas existentes."}; material: {"name":"Luminaria exterior · gris","status":"provisional","source":"Acabado visual aproximado; no especificación de proyecto."}; appearance: {"profileId":"ctx_light","name":"Luminaria exterior · gris","status":"criterio_visual","basis":"Acabado de contexto orientativo, sin especificación de obra."}; dimensions: {"documented":[],"assumed":[{"label":"Altura de poste","value":8,"unit":"m"},{"label":"Vuelo de brazo","value":1.4,"unit":"m"}],"geometry":[]}; classification: {"layerId":"context_furniture","layerName":"Entorno · aparcamientos y luminarias","function":"Luminaria del entorno · ilustrativa 36"}; visualLayer: {"id":"context_furniture","name":"Entorno · aparcamientos y luminarias","defaultVisible":false}; representationKind: entorno_ilustrativo; quantityEligible: no; positioning: {"Sistema":"ETRS89 / UTM 29N · metros","Origen del modelo":"X 729400 · Y 4301550 · Z 285 m","Alcance":"Hasta 200 m desde el lindero del proyecto; solo exterior de parcela","Planta":"Distribución ilustrativa autorizada","Altimetría":"Plano ajustado a 213 puntos XYZ de aceras, extrapolado al resto del contexto; no es un MDT levantado"}; issues: ["Contexto para lectura del emplazamiento; planta derivada de cartografía, cotas y detalles simplificados. No para construcción ni mediciones de obra.","Las mediciones en el entorno expresan la geometría representada y conservan la precisión de su fuente."]; conceptual: {"enabled":true,"basis":"Distribución aproximada autorizada. No acredita la posición ni el número real de plazas o farolas existentes.","pending":["Posición real del mobiliario","Dimensiones y niveles definitivos"]}; geometryMetrics: {"boundingBoxM":{"min":[254.794604,-129.335134,3.104323],"max":[256.702656,-128.830829,11.214323]},"extentsM":[1.908052,0.504305,8.11],"meshSurfaceM2":5.532365,"meshVolumeM3":0.181319,"closedSolid":true,"basis":"Entorno de coordinación: trazados derivados de las fuentes indicadas por elemento; cotas, espesores, acabados y mobiliario orientativos cuando no están documentados. No acredita propiedad, servidumbres ni cantidades de obra y no es una base de construcción."}
JH_Trazabilidad - Origen: Indicación del cliente · entorno de 200 m con aparcamientos y luminarias ilustrativos; Estado: provisional; Capa BIM: Entorno · aparcamientos y luminarias; Mediciones de obra: Excluido; Identificador: CTX-LIGHT-36; Categoria: Luminaria del entorno · ilustrativa 36; ClaseIFC: IfcLightFixture; EstadoDeInformacion: provisional; DocumentoFuente: {"documentId":"JH-CLIENT-CONTEXT-20260909","title":"Indicación del cliente · entorno de 200 m con aparcamientos y luminarias ilustrativos","date":"2026-09-09","note":"Distribución aproximada autorizada. No acredita la posición ni el número real de plazas o farolas existentes."}; IncidenciasPendientes: ["Contexto para lectura del emplazamiento; planta derivada de cartografía, cotas y detalles simplificados. No para construcción ni mediciones de obra.","Las mediciones en el entorno expresan la geometría representada y conservan la precisión de su fuente."]; UsoDeLasMagnitudes: Entorno de coordinación: trazados derivados de las fuentes indicadas por elemento; cotas, espesores, acabados y mobiliario orientativos cuando no están documentados. No acredita propiedad, servidumbres ni cantidades de obra y no es una base de construcción.
JH_CriterioDePosicion - PosicionYEstado: {"Sistema":"ETRS89 / UTM 29N · metros","Origen del modelo":"X 729400 · Y 4301550 · Z 285 m","Alcance":"Hasta 200 m desde el lindero del proyecto; solo exterior de parcela","Planta":"Distribución ilustrativa autorizada","Altimetría":"Plano ajustado a 213 puntos XYZ de aceras, extrapolado al resto del contexto; no es un MDT levantado"}
JH_EvidenciaDeMaterial - name: Luminaria exterior · gris; status: provisional; source: Acabado visual aproximado; no especificación de proyecto.
JH_CapaBIM - IdentificadorCapa: context_furniture; NombreCapa: Entorno · aparcamientos y luminarias; Funcion: Luminaria del entorno · ilustrativa 36; VisibilidadInicial: no
JH_EntornoContexto - Estado: provisional; Origen: {"documentId":"JH-CLIENT-CONTEXT-20260909","title":"Indicación del cliente · entorno de 200 m con aparcamientos y luminarias ilustrativos","date":"2026-09-09","note":"Distribución aproximada autorizada. No acredita la posición ni el número real de plazas o farolas existentes."}; Posicion: {"Sistema":"ETRS89 / UTM 29N · metros","Origen del modelo":"X 729400 · Y 4301550 · Z 285 m","Alcance":"Hasta 200 m desde el lindero del proyecto; solo exterior de parcela","Planta":"Distribución ilustrativa autorizada","Altimetría":"Plano ajustado a 213 puntos XYZ de aceras, extrapolado al resto del contexto; no es un MDT levantado"}; DimensionesSupuestas: [{"label":"Altura de poste","value":8,"unit":"m"},{"label":"Vuelo de brazo","value":1.4,"unit":"m"}]; IncluirEnMediciones: no; EsquemaIlustrativo: yes; Criterio: Entorno de coordinación: trazados derivados de las fuentes indicadas por elemento; cotas, espesores, acabados y mobiliario orientativos cuando no están documentados. No acredita propiedad, servidumbres ni cantidades de obra y no es una base de construcción.
JH_EsquemaProvisional - Estado: No para construcción; Origen: {"documentId":"JH-CLIENT-CONTEXT-20260909","title":"Indicación del cliente · entorno de 200 m con aparcamientos y luminarias ilustrativos","date":"2026-09-09","note":"Distribución aproximada autorizada. No acredita la posición ni el número real de plazas o farolas existentes."}; DimensionesSupuestas: [{"label":"Altura de poste","value":8,"unit":"m"},{"label":"Vuelo de brazo","value":1.4,"unit":"m"}]; Posicion: {"Sistema":"ETRS89 / UTM 29N · metros","Origen del modelo":"X 729400 · Y 4301550 · Z 285 m","Alcance":"Hasta 200 m desde el lindero del proyecto; solo exterior de parcela","Planta":"Distribución ilustrativa autorizada","Altimetría":"Plano ajustado a 213 puntos XYZ de aceras, extrapolado al resto del contexto; no es un MDT levantado"}; IncluirEnMediciones: no; Criterio: {"enabled":true,"basis":"Distribución aproximada autorizada. No acredita la posición ni el número real de plazas o farolas existentes.","pending":["Posición real del mobiliario","Dimensiones y niveles definitivos"]}

# IfcLightFixture: Luminaria del entorno · ilustrativa 4
In: Parcela industrial Jinhong
Description: Entorno de coordinación: trazados derivados de las fuentes indicadas por elemento; cotas, espesores, acabados y mobiliario orientativos cuando no están documentados. No acredita propiedad, servidumbres ni cantidades de obra y no es una base de construcción.; PredefinedType: USERDEFINED; Document: Indicación del cliente · entorno de 200 m con aparcamientos y luminarias ilustrativos; Entorno de Expacio Mérida · Catastro INSPIRE, PNOA y levantamiento Berrio; Levantamiento Berrio · parcelas I-27 Vial 3 e I-18 Vial 4; IGN · ortofotografía PNOA de máxima actualidad; Group: BIM · Entorno · aparcamientos y luminarias
JH_InformacionBIM - buildingId: context; buildingName: Entorno exterior de la parcela; level: Exterior · contexto de 200 m; category: Luminaria del entorno · ilustrativa 4; ifcClass: IfcLightFixture; status: provisional; source: {"documentId":"JH-CLIENT-CONTEXT-20260909","title":"Indicación del cliente · entorno de 200 m con aparcamientos y luminarias ilustrativos","date":"2026-09-09","note":"Distribución aproximada autorizada. No acredita la posición ni el número real de plazas o farolas existentes."}; material: {"name":"Luminaria exterior · gris","status":"provisional","source":"Acabado visual aproximado; no especificación de proyecto."}; appearance: {"profileId":"ctx_light","name":"Luminaria exterior · gris","status":"criterio_visual","basis":"Acabado de contexto orientativo, sin especificación de obra."}; dimensions: {"documented":[],"assumed":[{"label":"Altura de poste","value":8,"unit":"m"},{"label":"Vuelo de brazo","value":1.4,"unit":"m"}],"geometry":[]}; classification: {"layerId":"context_furniture","layerName":"Entorno · aparcamientos y luminarias","function":"Luminaria del entorno · ilustrativa 4"}; visualLayer: {"id":"context_furniture","name":"Entorno · aparcamientos y luminarias","defaultVisible":false}; representationKind: entorno_ilustrativo; quantityEligible: no; positioning: {"Sistema":"ETRS89 / UTM 29N · metros","Origen del modelo":"X 729400 · Y 4301550 · Z 285 m","Alcance":"Hasta 200 m desde el lindero del proyecto; solo exterior de parcela","Planta":"Distribución ilustrativa autorizada","Altimetría":"Plano ajustado a 213 puntos XYZ de aceras, extrapolado al resto del contexto; no es un MDT levantado"}; issues: ["Contexto para lectura del emplazamiento; planta derivada de cartografía, cotas y detalles simplificados. No para construcción ni mediciones de obra.","Las mediciones en el entorno expresan la geometría representada y conservan la precisión de su fuente."]; conceptual: {"enabled":true,"basis":"Distribución aproximada autorizada. No acredita la posición ni el número real de plazas o farolas existentes.","pending":["Posición real del mobiliario","Dimensiones y niveles definitivos"]}; geometryMetrics: {"boundingBoxM":{"min":[-40.242284,-45.459594,-0.027062],"max":[-38.332201,-44.97736,8.082938]},"extentsM":[1.910083,0.482234,8.11],"meshSurfaceM2":5.532362,"meshVolumeM3":0.181319,"closedSolid":true,"basis":"Entorno de coordinación: trazados derivados de las fuentes indicadas por elemento; cotas, espesores, acabados y mobiliario orientativos cuando no están documentados. No acredita propiedad, servidumbres ni cantidades de obra y no es una base de construcción."}
JH_Trazabilidad - Origen: Indicación del cliente · entorno de 200 m con aparcamientos y luminarias ilustrativos; Estado: provisional; Capa BIM: Entorno · aparcamientos y luminarias; Mediciones de obra: Excluido; Identificador: CTX-LIGHT-04; Categoria: Luminaria del entorno · ilustrativa 4; ClaseIFC: IfcLightFixture; EstadoDeInformacion: provisional; DocumentoFuente: {"documentId":"JH-CLIENT-CONTEXT-20260909","title":"Indicación del cliente · entorno de 200 m con aparcamientos y luminarias ilustrativos","date":"2026-09-09","note":"Distribución aproximada autorizada. No acredita la posición ni el número real de plazas o farolas existentes."}; IncidenciasPendientes: ["Contexto para lectura del emplazamiento; planta derivada de cartografía, cotas y detalles simplificados. No para construcción ni mediciones de obra.","Las mediciones en el entorno expresan la geometría representada y conservan la precisión de su fuente."]; UsoDeLasMagnitudes: Entorno de coordinación: trazados derivados de las fuentes indicadas por elemento; cotas, espesores, acabados y mobiliario orientativos cuando no están documentados. No acredita propiedad, servidumbres ni cantidades de obra y no es una base de construcción.
JH_CriterioDePosicion - PosicionYEstado: {"Sistema":"ETRS89 / UTM 29N · metros","Origen del modelo":"X 729400 · Y 4301550 · Z 285 m","Alcance":"Hasta 200 m desde el lindero del proyecto; solo exterior de parcela","Planta":"Distribución ilustrativa autorizada","Altimetría":"Plano ajustado a 213 puntos XYZ de aceras, extrapolado al resto del contexto; no es un MDT levantado"}
JH_EvidenciaDeMaterial - name: Luminaria exterior · gris; status: provisional; source: Acabado visual aproximado; no especificación de proyecto.
JH_CapaBIM - IdentificadorCapa: context_furniture; NombreCapa: Entorno · aparcamientos y luminarias; Funcion: Luminaria del entorno · ilustrativa 4; VisibilidadInicial: no
JH_EntornoContexto - Estado: provisional; Origen: {"documentId":"JH-CLIENT-CONTEXT-20260909","title":"Indicación del cliente · entorno de 200 m con aparcamientos y luminarias ilustrativos","date":"2026-09-09","note":"Distribución aproximada autorizada. No acredita la posición ni el número real de plazas o farolas existentes."}; Posicion: {"Sistema":"ETRS89 / UTM 29N · metros","Origen del modelo":"X 729400 · Y 4301550 · Z 285 m","Alcance":"Hasta 200 m desde el lindero del proyecto; solo exterior de parcela","Planta":"Distribución ilustrativa autorizada","Altimetría":"Plano ajustado a 213 puntos XYZ de aceras, extrapolado al resto del contexto; no es un MDT levantado"}; DimensionesSupuestas: [{"label":"Altura de poste","value":8,"unit":"m"},{"label":"Vuelo de brazo","value":1.4,"unit":"m"}]; IncluirEnMediciones: no; EsquemaIlustrativo: yes; Criterio: Entorno de coordinación: trazados derivados de las fuentes indicadas por elemento; cotas, espesores, acabados y mobiliario orientativos cuando no están documentados. No acredita propiedad, servidumbres ni cantidades de obra y no es una base de construcción.
JH_EsquemaProvisional - Estado: No para construcción; Origen: {"documentId":"JH-CLIENT-CONTEXT-20260909","title":"Indicación del cliente · entorno de 200 m con aparcamientos y luminarias ilustrativos","date":"2026-09-09","note":"Distribución aproximada autorizada. No acredita la posición ni el número real de plazas o farolas existentes."}; DimensionesSupuestas: [{"label":"Altura de poste","value":8,"unit":"m"},{"label":"Vuelo de brazo","value":1.4,"unit":"m"}]; Posicion: {"Sistema":"ETRS89 / UTM 29N · metros","Origen del modelo":"X 729400 · Y 4301550 · Z 285 m","Alcance":"Hasta 200 m desde el lindero del proyecto; solo exterior de parcela","Planta":"Distribución ilustrativa autorizada","Altimetría":"Plano ajustado a 213 puntos XYZ de aceras, extrapolado al resto del contexto; no es un MDT levantado"}; IncluirEnMediciones: no; Criterio: {"enabled":true,"basis":"Distribución aproximada autorizada. No acredita la posición ni el número real de plazas o farolas existentes.","pending":["Posición real del mobiliario","Dimensiones y niveles definitivos"]}

# IfcLightFixture: Luminaria del entorno · ilustrativa 5
In: Parcela industrial Jinhong
Description: Entorno de coordinación: trazados derivados de las fuentes indicadas por elemento; cotas, espesores, acabados y mobiliario orientativos cuando no están documentados. No acredita propiedad, servidumbres ni cantidades de obra y no es una base de construcción.; PredefinedType: USERDEFINED; Document: Indicación del cliente · entorno de 200 m con aparcamientos y luminarias ilustrativos; Entorno de Expacio Mérida · Catastro INSPIRE, PNOA y levantamiento Berrio; Levantamiento Berrio · parcelas I-27 Vial 3 e I-18 Vial 4; IGN · ortofotografía PNOA de máxima actualidad; Group: BIM · Entorno · aparcamientos y luminarias
JH_InformacionBIM - buildingId: context; buildingName: Entorno exterior de la parcela; level: Exterior · contexto de 200 m; category: Luminaria del entorno · ilustrativa 5; ifcClass: IfcLightFixture; status: provisional; source: {"documentId":"JH-CLIENT-CONTEXT-20260909","title":"Indicación del cliente · entorno de 200 m con aparcamientos y luminarias ilustrativos","date":"2026-09-09","note":"Distribución aproximada autorizada. No acredita la posición ni el número real de plazas o farolas existentes."}; material: {"name":"Luminaria exterior · gris","status":"provisional","source":"Acabado visual aproximado; no especificación de proyecto."}; appearance: {"profileId":"ctx_light","name":"Luminaria exterior · gris","status":"criterio_visual","basis":"Acabado de contexto orientativo, sin especificación de obra."}; dimensions: {"documented":[],"assumed":[{"label":"Altura de poste","value":8,"unit":"m"},{"label":"Vuelo de brazo","value":1.4,"unit":"m"}],"geometry":[]}; classification: {"layerId":"context_furniture","layerName":"Entorno · aparcamientos y luminarias","function":"Luminaria del entorno · ilustrativa 5"}; visualLayer: {"id":"context_furniture","name":"Entorno · aparcamientos y luminarias","defaultVisible":false}; representationKind: entorno_ilustrativo; quantityEligible: no; positioning: {"Sistema":"ETRS89 / UTM 29N · metros","Origen del modelo":"X 729400 · Y 4301550 · Z 285 m","Alcance":"Hasta 200 m desde el lindero del proyecto; solo exterior de parcela","Planta":"Distribución ilustrativa autorizada","Altimetría":"Plano ajustado a 213 puntos XYZ de aceras, extrapolado al resto del contexto; no es un MDT levantado"}; issues: ["Contexto para lectura del emplazamiento; planta derivada de cartografía, cotas y detalles simplificados. No para construcción ni mediciones de obra.","Las mediciones en el entorno expresan la geometría representada y conservan la precisión de su fuente."]; conceptual: {"enabled":true,"basis":"Distribución aproximada autorizada. No acredita la posición ni el número real de plazas o farolas existentes.","pending":["Posición real del mobiliario","Dimensiones y niveles definitivos"]}; geometryMetrics: {"boundingBoxM":{"min":[-16.103517,-15.465736,0.343991],"max":[-14.193434,-14.983503,8.453991]},"extentsM":[1.910083,0.482233,8.11],"meshSurfaceM2":5.532364,"meshVolumeM3":0.181319,"closedSolid":true,"basis":"Entorno de coordinación: trazados derivados de las fuentes indicadas por elemento; cotas, espesores, acabados y mobiliario orientativos cuando no están documentados. No acredita propiedad, servidumbres ni cantidades de obra y no es una base de construcción."}
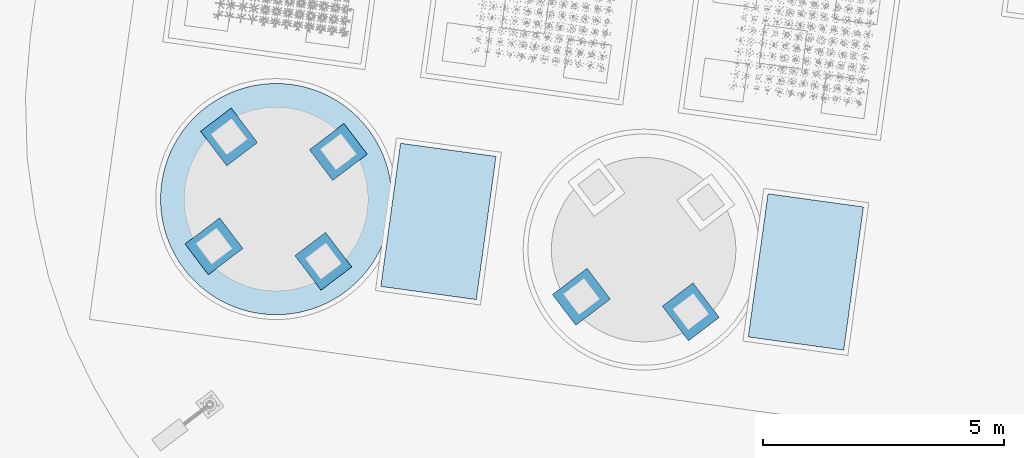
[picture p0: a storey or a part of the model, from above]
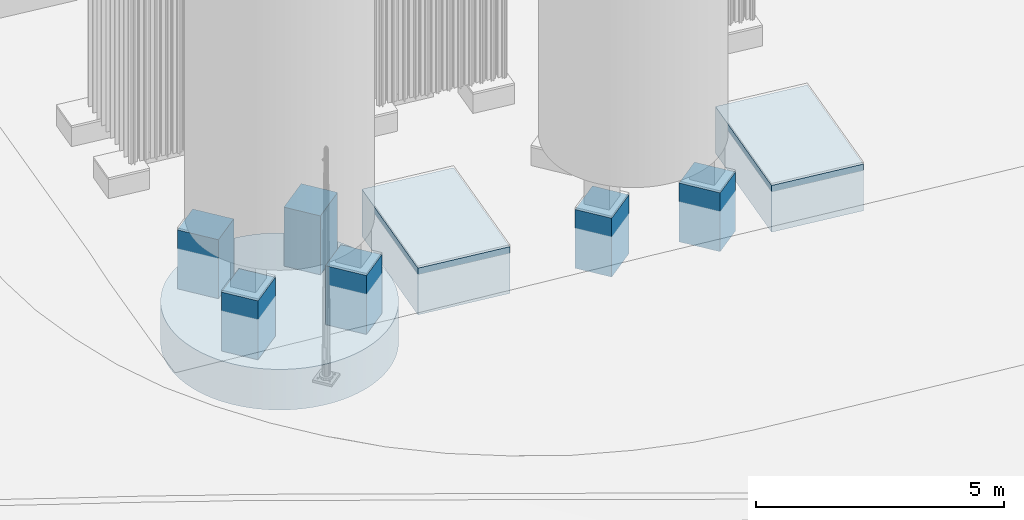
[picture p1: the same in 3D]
Properties of the parts of a building model (IFC4), part 94 of 134

# IfcLightFixture: Luminaria del entorno · ilustrativa 5
JH_Trazabilidad - Origen: Indicación del cliente · entorno de 200 m con aparcamientos y luminarias ilustrativos; Estado: provisional; Capa BIM: Entorno · aparcamientos y luminarias; Mediciones de obra: Excluido; Identificador: CTX-LIGHT-05; Categoria: Luminaria del entorno · ilustrativa 5; ClaseIFC: IfcLightFixture; EstadoDeInformacion: provisional; DocumentoFuente: {"documentId":"JH-CLIENT-CONTEXT-20260909","title":"Indicación del cliente · entorno de 200 m con aparcamientos y luminarias ilustrativos","date":"2026-09-09","note":"Distribución aproximada autorizada. No acredita la posición ni el número real de plazas o farolas existentes."}; IncidenciasPendientes: ["Contexto para lectura del emplazamiento; planta derivada de cartografía, cotas y detalles simplificados. No para construcción ni mediciones de obra.","Las mediciones en el entorno expresan la geometría representada y conservan la precisión de su fuente."]; UsoDeLasMagnitudes: Entorno de coordinación: trazados derivados de las fuentes indicadas por elemento; cotas, espesores, acabados y mobiliario orientativos cuando no están documentados. No acredita propiedad, servidumbres ni cantidades de obra y no es una base de construcción.
JH_CriterioDePosicion - PosicionYEstado: {"Sistema":"ETRS89 / UTM 29N · metros","Origen del modelo":"X 729400 · Y 4301550 · Z 285 m","Alcance":"Hasta 200 m desde el lindero del proyecto; solo exterior de parcela","Planta":"Distribución ilustrativa autorizada","Altimetría":"Plano ajustado a 213 puntos XYZ de aceras, extrapolado al resto del contexto; no es un MDT levantado"}
JH_EvidenciaDeMaterial - name: Luminaria exterior · gris; status: provisional; source: Acabado visual aproximado; no especificación de proyecto.
JH_CapaBIM - IdentificadorCapa: context_furniture; NombreCapa: Entorno · aparcamientos y luminarias; Funcion: Luminaria del entorno · ilustrativa 5; VisibilidadInicial: no
JH_EntornoContexto - Estado: provisional; Origen: {"documentId":"JH-CLIENT-CONTEXT-20260909","title":"Indicación del cliente · entorno de 200 m con aparcamientos y luminarias ilustrativos","date":"2026-09-09","note":"Distribución aproximada autorizada. No acredita la posición ni el número real de plazas o farolas existentes."}; Posicion: {"Sistema":"ETRS89 / UTM 29N · metros","Origen del modelo":"X 729400 · Y 4301550 · Z 285 m","Alcance":"Hasta 200 m desde el lindero del proyecto; solo exterior de parcela","Planta":"Distribución ilustrativa autorizada","Altimetría":"Plano ajustado a 213 puntos XYZ de aceras, extrapolado al resto del contexto; no es un MDT levantado"}; DimensionesSupuestas: [{"label":"Altura de poste","value":8,"unit":"m"},{"label":"Vuelo de brazo","value":1.4,"unit":"m"}]; IncluirEnMediciones: no; EsquemaIlustrativo: yes; Criterio: Entorno de coordinación: trazados derivados de las fuentes indicadas por elemento; cotas, espesores, acabados y mobiliario orientativos cuando no están documentados. No acredita propiedad, servidumbres ni cantidades de obra y no es una base de construcción.
JH_EsquemaProvisional - Estado: No para construcción; Origen: {"documentId":"JH-CLIENT-CONTEXT-20260909","title":"Indicación del cliente · entorno de 200 m con aparcamientos y luminarias ilustrativos","date":"2026-09-09","note":"Distribución aproximada autorizada. No acredita la posición ni el número real de plazas o farolas existentes."}; DimensionesSupuestas: [{"label":"Altura de poste","value":8,"unit":"m"},{"label":"Vuelo de brazo","value":1.4,"unit":"m"}]; Posicion: {"Sistema":"ETRS89 / UTM 29N · metros","Origen del modelo":"X 729400 · Y 4301550 · Z 285 m","Alcance":"Hasta 200 m desde el lindero del proyecto; solo exterior de parcela","Planta":"Distribución ilustrativa autorizada","Altimetría":"Plano ajustado a 213 puntos XYZ de aceras, extrapolado al resto del contexto; no es un MDT levantado"}; IncluirEnMediciones: no; Criterio: {"enabled":true,"basis":"Distribución aproximada autorizada. No acredita la posición ni el número real de plazas o farolas existentes.","pending":["Posición real del mobiliario","Dimensiones y niveles definitivos"]}

# IfcLightFixture: Luminaria del entorno · ilustrativa 6
In: Parcela industrial Jinhong
Description: Entorno de coordinación: trazados derivados de las fuentes indicadas por elemento; cotas, espesores, acabados y mobiliario orientativos cuando no están documentados. No acredita propiedad, servidumbres ni cantidades de obra y no es una base de construcción.; PredefinedType: USERDEFINED; Document: Indicación del cliente · entorno de 200 m con aparcamientos y luminarias ilustrativos; Entorno de Expacio Mérida · Catastro INSPIRE, PNOA y levantamiento Berrio; Levantamiento Berrio · parcelas I-27 Vial 3 e I-18 Vial 4; IGN · ortofotografía PNOA de máxima actualidad; Group: BIM · Entorno · aparcamientos y luminarias
JH_InformacionBIM - buildingId: context; buildingName: Entorno exterior de la parcela; level: Exterior · contexto de 200 m; category: Luminaria del entorno · ilustrativa 6; ifcClass: IfcLightFixture; status: provisional; source: {"documentId":"JH-CLIENT-CONTEXT-20260909","title":"Indicación del cliente · entorno de 200 m con aparcamientos y luminarias ilustrativos","date":"2026-09-09","note":"Distribución aproximada autorizada. No acredita la posición ni el número real de plazas o farolas existentes."}; material: {"name":"Luminaria exterior · gris","status":"provisional","source":"Acabado visual aproximado; no especificación de proyecto."}; appearance: {"profileId":"ctx_light","name":"Luminaria exterior · gris","status":"criterio_visual","basis":"Acabado de contexto orientativo, sin especificación de obra."}; dimensions: {"documented":[],"assumed":[{"label":"Altura de poste","value":8,"unit":"m"},{"label":"Vuelo de brazo","value":1.4,"unit":"m"}],"geometry":[]}; classification: {"layerId":"context_furniture","layerName":"Entorno · aparcamientos y luminarias","function":"Luminaria del entorno · ilustrativa 6"}; visualLayer: {"id":"context_furniture","name":"Entorno · aparcamientos y luminarias","defaultVisible":false}; representationKind: entorno_ilustrativo; quantityEligible: no; positioning: {"Sistema":"ETRS89 / UTM 29N · metros","Origen del modelo":"X 729400 · Y 4301550 · Z 285 m","Alcance":"Hasta 200 m desde el lindero del proyecto; solo exterior de parcela","Planta":"Distribución ilustrativa autorizada","Altimetría":"Plano ajustado a 213 puntos XYZ de aceras, extrapolado al resto del contexto; no es un MDT levantado"}; issues: ["Contexto para lectura del emplazamiento; planta derivada de cartografía, cotas y detalles simplificados. No para construcción ni mediciones de obra.","Las mediciones en el entorno expresan la geometría representada y conservan la precisión de su fuente."]; conceptual: {"enabled":true,"basis":"Distribución aproximada autorizada. No acredita la posición ni el número real de plazas o farolas existentes.","pending":["Posición real del mobiliario","Dimensiones y niveles definitivos"]}; geometryMetrics: {"boundingBoxM":{"min":[-38.060897,-13.530116,0.082941],"max":[-36.150814,-13.047882,8.192941]},"extentsM":[1.910083,0.482234,8.11],"meshSurfaceM2":5.532364,"meshVolumeM3":0.181319,"closedSolid":true,"basis":"Entorno de coordinación: trazados derivados de las fuentes indicadas por elemento; cotas, espesores, acabados y mobiliario orientativos cuando no están documentados. No acredita propiedad, servidumbres ni cantidades de obra y no es una base de construcción."}
JH_Trazabilidad - Origen: Indicación del cliente · entorno de 200 m con aparcamientos y luminarias ilustrativos; Estado: provisional; Capa BIM: Entorno · aparcamientos y luminarias; Mediciones de obra: Excluido; Identificador: CTX-LIGHT-06; Categoria: Luminaria del entorno · ilustrativa 6; ClaseIFC: IfcLightFixture; EstadoDeInformacion: provisional; DocumentoFuente: {"documentId":"JH-CLIENT-CONTEXT-20260909","title":"Indicación del cliente · entorno de 200 m con aparcamientos y luminarias ilustrativos","date":"2026-09-09","note":"Distribución aproximada autorizada. No acredita la posición ni el número real de plazas o farolas existentes."}; IncidenciasPendientes: ["Contexto para lectura del emplazamiento; planta derivada de cartografía, cotas y detalles simplificados. No para construcción ni mediciones de obra.","Las mediciones en el entorno expresan la geometría representada y conservan la precisión de su fuente."]; UsoDeLasMagnitudes: Entorno de coordinación: trazados derivados de las fuentes indicadas por elemento; cotas, espesores, acabados y mobiliario orientativos cuando no están documentados. No acredita propiedad, servidumbres ni cantidades de obra y no es una base de construcción.
JH_CriterioDePosicion - PosicionYEstado: {"Sistema":"ETRS89 / UTM 29N · metros","Origen del modelo":"X 729400 · Y 4301550 · Z 285 m","Alcance":"Hasta 200 m desde el lindero del proyecto; solo exterior de parcela","Planta":"Distribución ilustrativa autorizada","Altimetría":"Plano ajustado a 213 puntos XYZ de aceras, extrapolado al resto del contexto; no es un MDT levantado"}
JH_EvidenciaDeMaterial - name: Luminaria exterior · gris; status: provisional; source: Acabado visual aproximado; no especificación de proyecto.
JH_CapaBIM - IdentificadorCapa: context_furniture; NombreCapa: Entorno · aparcamientos y luminarias; Funcion: Luminaria del entorno · ilustrativa 6; VisibilidadInicial: no
JH_EntornoContexto - Estado: provisional; Origen: {"documentId":"JH-CLIENT-CONTEXT-20260909","title":"Indicación del cliente · entorno de 200 m con aparcamientos y luminarias ilustrativos","date":"2026-09-09","note":"Distribución aproximada autorizada. No acredita la posición ni el número real de plazas o farolas existentes."}; Posicion: {"Sistema":"ETRS89 / UTM 29N · metros","Origen del modelo":"X 729400 · Y 4301550 · Z 285 m","Alcance":"Hasta 200 m desde el lindero del proyecto; solo exterior de parcela","Planta":"Distribución ilustrativa autorizada","Altimetría":"Plano ajustado a 213 puntos XYZ de aceras, extrapolado al resto del contexto; no es un MDT levantado"}; DimensionesSupuestas: [{"label":"Altura de poste","value":8,"unit":"m"},{"label":"Vuelo de brazo","value":1.4,"unit":"m"}]; IncluirEnMediciones: no; EsquemaIlustrativo: yes; Criterio: Entorno de coordinación: trazados derivados de las fuentes indicadas por elemento; cotas, espesores, acabados y mobiliario orientativos cuando no están documentados. No acredita propiedad, servidumbres ni cantidades de obra y no es una base de construcción.
JH_EsquemaProvisional - Estado: No para construcción; Origen: {"documentId":"JH-CLIENT-CONTEXT-20260909","title":"Indicación del cliente · entorno de 200 m con aparcamientos y luminarias ilustrativos","date":"2026-09-09","note":"Distribución aproximada autorizada. No acredita la posición ni el número real de plazas o farolas existentes."}; DimensionesSupuestas: [{"label":"Altura de poste","value":8,"unit":"m"},{"label":"Vuelo de brazo","value":1.4,"unit":"m"}]; Posicion: {"Sistema":"ETRS89 / UTM 29N · metros","Origen del modelo":"X 729400 · Y 4301550 · Z 285 m","Alcance":"Hasta 200 m desde el lindero del proyecto; solo exterior de parcela","Planta":"Distribución ilustrativa autorizada","Altimetría":"Plano ajustado a 213 puntos XYZ de aceras, extrapolado al resto del contexto; no es un MDT levantado"}; IncluirEnMediciones: no; Criterio: {"enabled":true,"basis":"Distribución aproximada autorizada. No acredita la posición ni el número real de plazas o farolas existentes.","pending":["Posición real del mobiliario","Dimensiones y niveles definitivos"]}

# IfcLightFixture: Luminaria del entorno · ilustrativa 7
In: Parcela industrial Jinhong
Description: Entorno de coordinación: trazados derivados de las fuentes indicadas por elemento; cotas, espesores, acabados y mobiliario orientativos cuando no están documentados. No acredita propiedad, servidumbres ni cantidades de obra y no es una base de construcción.; PredefinedType: USERDEFINED; Document: Indicación del cliente · entorno de 200 m con aparcamientos y luminarias ilustrativos; Entorno de Expacio Mérida · Catastro INSPIRE, PNOA y levantamiento Berrio; Levantamiento Berrio · parcelas I-27 Vial 3 e I-18 Vial 4; IGN · ortofotografía PNOA de máxima actualidad; Group: BIM · Entorno · aparcamientos y luminarias
JH_InformacionBIM - buildingId: context; buildingName: Entorno exterior de la parcela; level: Exterior · contexto de 200 m; category: Luminaria del entorno · ilustrativa 7; ifcClass: IfcLightFixture; status: provisional; source: {"documentId":"JH-CLIENT-CONTEXT-20260909","title":"Indicación del cliente · entorno de 200 m con aparcamientos y luminarias ilustrativos","date":"2026-09-09","note":"Distribución aproximada autorizada. No acredita la posición ni el número real de plazas o farolas existentes."}; material: {"name":"Luminaria exterior · gris","status":"provisional","source":"Acabado visual aproximado; no especificación de proyecto."}; appearance: {"profileId":"ctx_light","name":"Luminaria exterior · gris","status":"criterio_visual","basis":"Acabado de contexto orientativo, sin especificación de obra."}; dimensions: {"documented":[],"assumed":[{"label":"Altura de poste","value":8,"unit":"m"},{"label":"Vuelo de brazo","value":1.4,"unit":"m"}],"geometry":[]}; classification: {"layerId":"context_furniture","layerName":"Entorno · aparcamientos y luminarias","function":"Luminaria del entorno · ilustrativa 7"}; visualLayer: {"id":"context_furniture","name":"Entorno · aparcamientos y luminarias","defaultVisible":false}; representationKind: entorno_ilustrativo; quantityEligible: no; positioning: {"Sistema":"ETRS89 / UTM 29N · metros","Origen del modelo":"X 729400 · Y 4301550 · Z 285 m","Alcance":"Hasta 200 m desde el lindero del proyecto; solo exterior de parcela","Planta":"Distribución ilustrativa autorizada","Altimetría":"Plano ajustado a 213 puntos XYZ de aceras, extrapolado al resto del contexto; no es un MDT levantado"}; issues: ["Contexto para lectura del emplazamiento; planta derivada de cartografía, cotas y detalles simplificados. No para construcción ni mediciones de obra.","Las mediciones en el entorno expresan la geometría representada y conservan la precisión de su fuente."]; conceptual: {"enabled":true,"basis":"Distribución aproximada autorizada. No acredita la posición ni el número real de plazas o farolas existentes.","pending":["Posición real del mobiliario","Dimensiones y niveles definitivos"]}; geometryMetrics: {"boundingBoxM":{"min":[3.100568,143.379966,0.986211],"max":[5.009879,143.871047,9.096211]},"extentsM":[1.909311,0.491081,8.11],"meshSurfaceM2":5.532364,"meshVolumeM3":0.181319,"closedSolid":true,"basis":"Entorno de coordinación: trazados derivados de las fuentes indicadas por elemento; cotas, espesores, acabados y mobiliario orientativos cuando no están documentados. No acredita propiedad, servidumbres ni cantidades de obra y no es una base de construcción."}
JH_Trazabilidad - Origen: Indicación del cliente · entorno de 200 m con aparcamientos y luminarias ilustrativos; Estado: provisional; Capa BIM: Entorno · aparcamientos y luminarias; Mediciones de obra: Excluido; Identificador: CTX-LIGHT-07; Categoria: Luminaria del entorno · ilustrativa 7; ClaseIFC: IfcLightFixture; EstadoDeInformacion: provisional; DocumentoFuente: {"documentId":"JH-CLIENT-CONTEXT-20260909","title":"Indicación del cliente · entorno de 200 m con aparcamientos y luminarias ilustrativos","date":"2026-09-09","note":"Distribución aproximada autorizada. No acredita la posición ni el número real de plazas o farolas existentes."}; IncidenciasPendientes: ["Contexto para lectura del emplazamiento; planta derivada de cartografía, cotas y detalles simplificados. No para construcción ni mediciones de obra.","Las mediciones en el entorno expresan la geometría representada y conservan la precisión de su fuente."]; UsoDeLasMagnitudes: Entorno de coordinación: trazados derivados de las fuentes indicadas por elemento; cotas, espesores, acabados y mobiliario orientativos cuando no están documentados. No acredita propiedad, servidumbres ni cantidades de obra y no es una base de construcción.
JH_CriterioDePosicion - PosicionYEstado: {"Sistema":"ETRS89 / UTM 29N · metros","Origen del modelo":"X 729400 · Y 4301550 · Z 285 m","Alcance":"Hasta 200 m desde el lindero del proyecto; solo exterior de parcela","Planta":"Distribución ilustrativa autorizada","Altimetría":"Plano ajustado a 213 puntos XYZ de aceras, extrapolado al resto del contexto; no es un MDT levantado"}
JH_EvidenciaDeMaterial - name: Luminaria exterior · gris; status: provisional; source: Acabado visual aproximado; no especificación de proyecto.
JH_CapaBIM - IdentificadorCapa: context_furniture; NombreCapa: Entorno · aparcamientos y luminarias; Funcion: Luminaria del entorno · ilustrativa 7; VisibilidadInicial: no
JH_EntornoContexto - Estado: provisional; Origen: {"documentId":"JH-CLIENT-CONTEXT-20260909","title":"Indicación del cliente · entorno de 200 m con aparcamientos y luminarias ilustrativos","date":"2026-09-09","note":"Distribución aproximada autorizada. No acredita la posición ni el número real de plazas o farolas existentes."}; Posicion: {"Sistema":"ETRS89 / UTM 29N · metros","Origen del modelo":"X 729400 · Y 4301550 · Z 285 m","Alcance":"Hasta 200 m desde el lindero del proyecto; solo exterior de parcela","Planta":"Distribución ilustrativa autorizada","Altimetría":"Plano ajustado a 213 puntos XYZ de aceras, extrapolado al resto del contexto; no es un MDT levantado"}; DimensionesSupuestas: [{"label":"Altura de poste","value":8,"unit":"m"},{"label":"Vuelo de brazo","value":1.4,"unit":"m"}]; IncluirEnMediciones: no; EsquemaIlustrativo: yes; Criterio: Entorno de coordinación: trazados derivados de las fuentes indicadas por elemento; cotas, espesores, acabados y mobiliario orientativos cuando no están documentados. No acredita propiedad, servidumbres ni cantidades de obra y no es una base de construcción.
JH_EsquemaProvisional - Estado: No para construcción; Origen: {"documentId":"JH-CLIENT-CONTEXT-20260909","title":"Indicación del cliente · entorno de 200 m con aparcamientos y luminarias ilustrativos","date":"2026-09-09","note":"Distribución aproximada autorizada. No acredita la posición ni el número real de plazas o farolas existentes."}; DimensionesSupuestas: [{"label":"Altura de poste","value":8,"unit":"m"},{"label":"Vuelo de brazo","value":1.4,"unit":"m"}]; Posicion: {"Sistema":"ETRS89 / UTM 29N · metros","Origen del modelo":"X 729400 · Y 4301550 · Z 285 m","Alcance":"Hasta 200 m desde el lindero del proyecto; solo exterior de parcela","Planta":"Distribución ilustrativa autorizada","Altimetría":"Plano ajustado a 213 puntos XYZ de aceras, extrapolado al resto del contexto; no es un MDT levantado"}; IncluirEnMediciones: no; Criterio: {"enabled":true,"basis":"Distribución aproximada autorizada. No acredita la posición ni el número real de plazas o farolas existentes.","pending":["Posición real del mobiliario","Dimensiones y niveles definitivos"]}

# IfcLightFixture: Luminaria del entorno · ilustrativa 8
In: Parcela industrial Jinhong
Description: Entorno de coordinación: trazados derivados de las fuentes indicadas por elemento; cotas, espesores, acabados y mobiliario orientativos cuando no están documentados. No acredita propiedad, servidumbres ni cantidades de obra y no es una base de construcción.; PredefinedType: USERDEFINED; Document: Indicación del cliente · entorno de 200 m con aparcamientos y luminarias ilustrativos; Entorno de Expacio Mérida · Catastro INSPIRE, PNOA y levantamiento Berrio; Levantamiento Berrio · parcelas I-27 Vial 3 e I-18 Vial 4; IGN · ortofotografía PNOA de máxima actualidad; Group: BIM · Entorno · aparcamientos y luminarias
JH_InformacionBIM - buildingId: context; buildingName: Entorno exterior de la parcela; level: Exterior · contexto de 200 m; category: Luminaria del entorno · ilustrativa 8; ifcClass: IfcLightFixture; status: provisional; source: {"documentId":"JH-CLIENT-CONTEXT-20260909","title":"Indicación del cliente · entorno de 200 m con aparcamientos y luminarias ilustrativos","date":"2026-09-09","note":"Distribución aproximada autorizada. No acredita la posición ni el número real de plazas o farolas existentes."}; material: {"name":"Luminaria exterior · gris","status":"provisional","source":"Acabado visual aproximado; no especificación de proyecto."}; appearance: {"profileId":"ctx_light","name":"Luminaria exterior · gris","status":"criterio_visual","basis":"Acabado de contexto orientativo, sin especificación de obra."}; dimensions: {"documented":[],"assumed":[{"label":"Altura de poste","value":8,"unit":"m"},{"label":"Vuelo de brazo","value":1.4,"unit":"m"}],"geometry":[]}; classification: {"layerId":"context_furniture","layerName":"Entorno · aparcamientos y luminarias","function":"Luminaria del entorno · ilustrativa 8"}; visualLayer: {"id":"context_furniture","name":"Entorno · aparcamientos y luminarias","defaultVisible":false}; representationKind: entorno_ilustrativo; quantityEligible: no; positioning: {"Sistema":"ETRS89 / UTM 29N · metros","Origen del modelo":"X 729400 · Y 4301550 · Z 285 m","Alcance":"Hasta 200 m desde el lindero del proyecto; solo exterior de parcela","Planta":"Distribución ilustrativa autorizada","Altimetría":"Plano ajustado a 213 puntos XYZ de aceras, extrapolado al resto del contexto; no es un MDT levantado"}; issues: ["Contexto para lectura del emplazamiento; planta derivada de cartografía, cotas y detalles simplificados. No para construcción ni mediciones de obra.","Las mediciones en el entorno expresan la geometría representada y conservan la precisión de su fuente."]; conceptual: {"enabled":true,"basis":"Distribución aproximada autorizada. No acredita la posición ni el número real de plazas o farolas existentes.","pending":["Posición real del mobiliario","Dimensiones y niveles definitivos"]}; geometryMetrics: {"boundingBoxM":{"min":[5.982427,175.249934,1.10402],"max":[7.891738,175.741016,9.21402]},"extentsM":[1.909311,0.491082,8.11],"meshSurfaceM2":5.532364,"meshVolumeM3":0.181319,"closedSolid":true,"basis":"Entorno de coordinación: trazados derivados de las fuentes indicadas por elemento; cotas, espesores, acabados y mobiliario orientativos cuando no están documentados. No acredita propiedad, servidumbres ni cantidades de obra y no es una base de construcción."}
JH_Trazabilidad - Origen: Indicación del cliente · entorno de 200 m con aparcamientos y luminarias ilustrativos; Estado: provisional; Capa BIM: Entorno · aparcamientos y luminarias; Mediciones de obra: Excluido; Identificador: CTX-LIGHT-08; Categoria: Luminaria del entorno · ilustrativa 8; ClaseIFC: IfcLightFixture; EstadoDeInformacion: provisional; DocumentoFuente: {"documentId":"JH-CLIENT-CONTEXT-20260909","title":"Indicación del cliente · entorno de 200 m con aparcamientos y luminarias ilustrativos","date":"2026-09-09","note":"Distribución aproximada autorizada. No acredita la posición ni el número real de plazas o farolas existentes."}; IncidenciasPendientes: ["Contexto para lectura del emplazamiento; planta derivada de cartografía, cotas y detalles simplificados. No para construcción ni mediciones de obra.","Las mediciones en el entorno expresan la geometría representada y conservan la precisión de su fuente."]; UsoDeLasMagnitudes: Entorno de coordinación: trazados derivados de las fuentes indicadas por elemento; cotas, espesores, acabados y mobiliario orientativos cuando no están documentados. No acredita propiedad, servidumbres ni cantidades de obra y no es una base de construcción.
JH_CriterioDePosicion - PosicionYEstado: {"Sistema":"ETRS89 / UTM 29N · metros","Origen del modelo":"X 729400 · Y 4301550 · Z 285 m","Alcance":"Hasta 200 m desde el lindero del proyecto; solo exterior de parcela","Planta":"Distribución ilustrativa autorizada","Altimetría":"Plano ajustado a 213 puntos XYZ de aceras, extrapolado al resto del contexto; no es un MDT levantado"}
JH_EvidenciaDeMaterial - name: Luminaria exterior · gris; status: provisional; source: Acabado visual aproximado; no especificación de proyecto.
JH_CapaBIM - IdentificadorCapa: context_furniture; NombreCapa: Entorno · aparcamientos y luminarias; Funcion: Luminaria del entorno · ilustrativa 8; VisibilidadInicial: no
JH_EntornoContexto - Estado: provisional; Origen: {"documentId":"JH-CLIENT-CONTEXT-20260909","title":"Indicación del cliente · entorno de 200 m con aparcamientos y luminarias ilustrativos","date":"2026-09-09","note":"Distribución aproximada autorizada. No acredita la posición ni el número real de plazas o farolas existentes."}; Posicion: {"Sistema":"ETRS89 / UTM 29N · metros","Origen del modelo":"X 729400 · Y 4301550 · Z 285 m","Alcance":"Hasta 200 m desde el lindero del proyecto; solo exterior de parcela","Planta":"Distribución ilustrativa autorizada","Altimetría":"Plano ajustado a 213 puntos XYZ de aceras, extrapolado al resto del contexto; no es un MDT levantado"}; DimensionesSupuestas: [{"label":"Altura de poste","value":8,"unit":"m"},{"label":"Vuelo de brazo","value":1.4,"unit":"m"}]; IncluirEnMediciones: no; EsquemaIlustrativo: yes; Criterio: Entorno de coordinación: trazados derivados de las fuentes indicadas por elemento; cotas, espesores, acabados y mobiliario orientativos cuando no están documentados. No acredita propiedad, servidumbres ni cantidades de obra y no es una base de construcción.
JH_EsquemaProvisional - Estado: No para construcción; Origen: {"documentId":"JH-CLIENT-CONTEXT-20260909","title":"Indicación del cliente · entorno de 200 m con aparcamientos y luminarias ilustrativos","date":"2026-09-09","note":"Distribución aproximada autorizada. No acredita la posición ni el número real de plazas o farolas existentes."}; DimensionesSupuestas: [{"label":"Altura de poste","value":8,"unit":"m"},{"label":"Vuelo de brazo","value":1.4,"unit":"m"}]; Posicion: {"Sistema":"ETRS89 / UTM 29N · metros","Origen del modelo":"X 729400 · Y 4301550 · Z 285 m","Alcance":"Hasta 200 m desde el lindero del proyecto; solo exterior de parcela","Planta":"Distribución ilustrativa autorizada","Altimetría":"Plano ajustado a 213 puntos XYZ de aceras, extrapolado al resto del contexto; no es un MDT levantado"}; IncluirEnMediciones: no; Criterio: {"enabled":true,"basis":"Distribución aproximada autorizada. No acredita la posición ni el número real de plazas o farolas existentes.","pending":["Posición real del mobiliario","Dimensiones y niveles definitivos"]}

# IfcLightFixture: Luminaria del entorno · ilustrativa 9
In: Parcela industrial Jinhong
Description: Entorno de coordinación: trazados derivados de las fuentes indicadas por elemento; cotas, espesores, acabados y mobiliario orientativos cuando no están documentados. No acredita propiedad, servidumbres ni cantidades de obra y no es una base de construcción.; PredefinedType: USERDEFINED; Document: Indicación del cliente · entorno de 200 m con aparcamientos y luminarias ilustrativos; Entorno de Expacio Mérida · Catastro INSPIRE, PNOA y levantamiento Berrio; Levantamiento Berrio · parcelas I-27 Vial 3 e I-18 Vial 4; IGN · ortofotografía PNOA de máxima actualidad; Group: BIM · Entorno · aparcamientos y luminarias
JH_InformacionBIM - buildingId: context; buildingName: Entorno exterior de la parcela; level: Exterior · contexto de 200 m; category: Luminaria del entorno · ilustrativa 9; ifcClass: IfcLightFixture; status: provisional; source: {"documentId":"JH-CLIENT-CONTEXT-20260909","title":"Indicación del cliente · entorno de 200 m con aparcamientos y luminarias ilustrativos","date":"2026-09-09","note":"Distribución aproximada autorizada. No acredita la posición ni el número real de plazas o farolas existentes."}; material: {"name":"Luminaria exterior · gris","status":"provisional","source":"Acabado visual aproximado; no especificación de proyecto."}; appearance: {"profileId":"ctx_light","name":"Luminaria exterior · gris","status":"criterio_visual","basis":"Acabado de contexto orientativo, sin especificación de obra."}; dimensions: {"documented":[],"assumed":[{"label":"Altura de poste","value":8,"unit":"m"},{"label":"Vuelo de brazo","value":1.4,"unit":"m"}],"geometry":[]}; classification: {"layerId":"context_furniture","layerName":"Entorno · aparcamientos y luminarias","function":"Luminaria del entorno · ilustrativa 9"}; visualLayer: {"id":"context_furniture","name":"Entorno · aparcamientos y luminarias","defaultVisible":false}; representationKind: entorno_ilustrativo; quantityEligible: no; positioning: {"Sistema":"ETRS89 / UTM 29N · metros","Origen del modelo":"X 729400 · Y 4301550 · Z 285 m","Alcance":"Hasta 200 m desde el lindero del proyecto; solo exterior de parcela","Planta":"Distribución ilustrativa autorizada","Altimetría":"Plano ajustado a 213 puntos XYZ de aceras, extrapolado al resto del contexto; no es un MDT levantado"}; issues: ["Contexto para lectura del emplazamiento; planta derivada de cartografía, cotas y detalles simplificados. No para construcción ni mediciones de obra.","Las mediciones en el entorno expresan la geometría representada y conservan la precisión de su fuente."]; conceptual: {"enabled":true,"basis":"Distribución aproximada autorizada. No acredita la posición ni el número real de plazas o farolas existentes.","pending":["Posición real del mobiliario","Dimensiones y niveles definitivos"]}; geometryMetrics: {"boundingBoxM":{"min":[8.30947,205.795335,1.211794],"max":[10.201888,206.410774,9.321794]},"extentsM":[1.892418,0.615439,8.11],"meshSurfaceM2":5.532364,"meshVolumeM3":0.181319,"closedSolid":true,"basis":"Entorno de coordinación: trazados derivados de las fuentes indicadas por elemento; cotas, espesores, acabados y mobiliario orientativos cuando no están documentados. No acredita propiedad, servidumbres ni cantidades de obra y no es una base de construcción."}
JH_Trazabilidad - Origen: Indicación del cliente · entorno de 200 m con aparcamientos y luminarias ilustrativos; Estado: provisional; Capa BIM: Entorno · aparcamientos y luminarias; Mediciones de obra: Excluido; Identificador: CTX-LIGHT-09; Categoria: Luminaria del entorno · ilustrativa 9; ClaseIFC: IfcLightFixture; EstadoDeInformacion: provisional; DocumentoFuente: {"documentId":"JH-CLIENT-CONTEXT-20260909","title":"Indicación del cliente · entorno de 200 m con aparcamientos y luminarias ilustrativos","date":"2026-09-09","note":"Distribución aproximada autorizada. No acredita la posición ni el número real de plazas o farolas existentes."}; IncidenciasPendientes: ["Contexto para lectura del emplazamiento; planta derivada de cartografía, cotas y detalles simplificados. No para construcción ni mediciones de obra.","Las mediciones en el entorno expresan la geometría representada y conservan la precisión de su fuente."]; UsoDeLasMagnitudes: Entorno de coordinación: trazados derivados de las fuentes indicadas por elemento; cotas, espesores, acabados y mobiliario orientativos cuando no están documentados. No acredita propiedad, servidumbres ni cantidades de obra y no es una base de construcción.
JH_CriterioDePosicion - PosicionYEstado: {"Sistema":"ETRS89 / UTM 29N · metros","Origen del modelo":"X 729400 · Y 4301550 · Z 285 m","Alcance":"Hasta 200 m desde el lindero del proyecto; solo exterior de parcela","Planta":"Distribución ilustrativa autorizada","Altimetría":"Plano ajustado a 213 puntos XYZ de aceras, extrapolado al resto del contexto; no es un MDT levantado"}
JH_EvidenciaDeMaterial - name: Luminaria exterior · gris; status: provisional; source: Acabado visual aproximado; no especificación de proyecto.
JH_CapaBIM - IdentificadorCapa: context_furniture; NombreCapa: Entorno · aparcamientos y luminarias; Funcion: Luminaria del entorno · ilustrativa 9; VisibilidadInicial: no
JH_EntornoContexto - Estado: provisional; Origen: {"documentId":"JH-CLIENT-CONTEXT-20260909","title":"Indicación del cliente · entorno de 200 m con aparcamientos y luminarias ilustrativos","date":"2026-09-09","note":"Distribución aproximada autorizada. No acredita la posición ni el número real de plazas o farolas existentes."}; Posicion: {"Sistema":"ETRS89 / UTM 29N · metros","Origen del modelo":"X 729400 · Y 4301550 · Z 285 m","Alcance":"Hasta 200 m desde el lindero del proyecto; solo exterior de parcela","Planta":"Distribución ilustrativa autorizada","Altimetría":"Plano ajustado a 213 puntos XYZ de aceras, extrapolado al resto del contexto; no es un MDT levantado"}; DimensionesSupuestas: [{"label":"Altura de poste","value":8,"unit":"m"},{"label":"Vuelo de brazo","value":1.4,"unit":"m"}]; IncluirEnMediciones: no; EsquemaIlustrativo: yes; Criterio: Entorno de coordinación: trazados derivados de las fuentes indicadas por elemento; cotas, espesores, acabados y mobiliario orientativos cuando no están documentados. No acredita propiedad, servidumbres ni cantidades de obra y no es una base de construcción.
JH_EsquemaProvisional - Estado: No para construcción; Origen: {"documentId":"JH-CLIENT-CONTEXT-20260909","title":"Indicación del cliente · entorno de 200 m con aparcamientos y luminarias ilustrativos","date":"2026-09-09","note":"Distribución aproximada autorizada. No acredita la posición ni el número real de plazas o farolas existentes."}; DimensionesSupuestas: [{"label":"Altura de poste","value":8,"unit":"m"},{"label":"Vuelo de brazo","value":1.4,"unit":"m"}]; Posicion: {"Sistema":"ETRS89 / UTM 29N · metros","Origen del modelo":"X 729400 · Y 4301550 · Z 285 m","Alcance":"Hasta 200 m desde el lindero del proyecto; solo exterior de parcela","Planta":"Distribución ilustrativa autorizada","Altimetría":"Plano ajustado a 213 puntos XYZ de aceras, extrapolado al resto del contexto; no es un MDT levantado"}; IncluirEnMediciones: no; Criterio: {"enabled":true,"basis":"Distribución aproximada autorizada. No acredita la posición ni el número real de plazas o farolas existentes.","pending":["Posición real del mobiliario","Dimensiones y niveles definitivos"]}

# IfcLightFixture: Luminaria exterior provisional (8)
In: Parcela industrial Jinhong
Description: Esquema provisional de coordinación autorizado por el cliente. Tuberías, soportes, alumbrado e hidrantes con dimensiones y posiciones orientativas; no para construcción ni cómputo de cantidades.; PredefinedType: USERDEFINED; Document: Ubicación aproximada de alumbrado e hidrantes solicitada para visualización; Urbanización existente en el modelo · contexto de implantación; Group: BIM · Alumbrado exterior
JH_InformacionBIM - buildingId: site; buildingName: Urbanización y parcela; level: Exterior · implantación provisional; category: Luminaria exterior provisional; ifcClass: IfcLightFixture; material: {"name":"No especificado","status":"unknown","source":"Sin ficha de producto confirmada; acabado gráfico de visualización."}; source: {"documentId":"JH-SITE-SERVICES-CONCEPT-20260908","title":"Ubicación aproximada de alumbrado e hidrantes solicitada para visualización","date":"2026-09-08","sheet":"Esquema provisional autorizado; sin plano de implantación de servicios","sourceScope":"Decisiones gráficas de modelado, no especificación del fabricante ni diseño técnico de instalaciones."}; contextSource: {"documentId":"JH-SITE-GROUND-CONTEXT-20260731","title":"Urbanización existente en el modelo · contexto de implantación","date":"2026-07-31","sheet":"Superficies representadas a partir de U004","sourceScope":"Solo contexto de suelo, viales y obstáculos; no documenta posición de luminarias o hidrantes."}; status: provisional; representationKind: conceptualVolume; conceptual: {"enabled":true,"userRequestedProvisional3D":true,"basis":"Propuesta aproximada de colocación en zonas libres junto a viales, autorizada para visualización.","status":"illustrative_not_documented","physicalHeightConfirmed":false,"quantityEligible":false,"notForConstruction":true,"warning":"Ubicación y dimensiones provisionales; no acredita cobertura contra incendios ni cálculo lumínico. Esquema de coordinación, no apto para construcción, compra ni mediciones."}; physicalHeightConfirmed: no; quantityEligible: no; heightStatus: illustrative_not_documented; layerId: site_lighting; classification: {"layerId":"site_lighting","layerName":"Alumbrado exterior","role":"Luminaria exterior provisional","basis":"Clasificación funcional de un esquema provisional."}; visualLayer: {"id":"site_lighting","name":"Alumbrado exterior","defaultVisible":true}; appearance: {"profileId":"amenity_v11_light_graphic","name":"Alumbrado provisional · metal gris","status":"esquema_provisional","basis":"Acabado metálico gris de identificación visual. Sin recubrimiento, potencia ni fotometría confirmados.","physicalMaterialUnchanged":true}; heightReference: {"valueM":6.0,"status":"illustrative_not_documented","sourceSupported":false,"sourceRef":"JH-SITE-SERVICES-CONCEPT-20260908","reason":"Altura elegida para esquema aproximado; no procede de una cota de fabricante.","sourceNote":"Ubicación y dimensiones provisionales; no acredita cobertura contra incendios ni cálculo lumínico. Esquema de coordinación, no apto para construcción, compra ni mediciones."}; issues: ["Ubicación y dimensiones provisionales; no acredita cobertura contra incendios ni cálculo lumínico. Esquema de coordinación, no apto para construcción, compra ni mediciones.","No se modelan cimentaciones enterradas, canalizaciones ni conexiones de servicio. Los anclajes visibles son elementos gráficos sin comprobación resistente.","Sin modelo, fabricante o especificación de prestaciones confirmados.","Sin potencia, flujo, distribución fotométrica, iluminancia, alimentación eléctrica o protección contra deslumbramiento calculados."]; coverageVerified: no; connectionsModeled: no; hydraulicCalculationProvided: no; lightingCalculationProvided: no
JH_Trazabilidad - Estado: Provisional; Altura ilustrativa (m): 6; Alcance: Ubicación y dimensiones provisionales; no acredita cobertura contra incendios ni cálculo lumínico. Esquema de coordinación, no apto para construcción, compra ni mediciones.; Aplicabilidad a mediciones: No; geometría gráfica sin cantidades certificadas.; Categoria: Luminaria exterior provisional; ClaseIFC: IfcLightFixture; EstadoDeInformacion: provisional; DocumentoFuente: {"documentId":"JH-SITE-SERVICES-CONCEPT-20260908","title":"Ubicación aproximada de alumbrado e hidrantes solicitada para visualización","date":"2026-09-08","sheet":"Esquema provisional autorizado; sin plano de implantación de servicios","sourceScope":"Decisiones gráficas de modelado, no especificación del fabricante ni diseño técnico de instalaciones."}; IncidenciasPendientes: ["Ubicación y dimensiones provisionales; no acredita cobertura contra incendios ni cálculo lumínico. Esquema de coordinación, no apto para construcción, compra ni mediciones.","No se modelan cimentaciones enterradas, canalizaciones ni conexiones de servicio. Los anclajes visibles son elementos gráficos sin comprobación resistente.","Sin modelo, fabricante o especificación de prestaciones confirmados.","Sin potencia, flujo, distribución fotométrica, iluminancia, alimentación eléctrica o protección contra deslumbramiento calculados."]; UsoDeLasMagnitudes: Esquema provisional de coordinación autorizado por el cliente. Tuberías, soportes, alumbrado e hidrantes con dimensiones y posiciones orientativas; no para construcción ni cómputo de cantidades.
JH_EvidenciaDeMaterial - name: No especificado; status: unknown; source: Sin ficha de producto confirmada; acabado gráfico de visualización.
JH_CapaBIM - IdentificadorCapa: site_lighting; NombreCapa: Alumbrado exterior; Funcion: Luminaria exterior provisional; VisibilidadInicial: yes
JH_EsquemaProvisional - Estado: No para construcción; Origen: {"documentId":"JH-SITE-SERVICES-CONCEPT-20260908","title":"Ubicación aproximada de alumbrado e hidrantes solicitada para visualización","date":"2026-09-08","sheet":"Esquema provisional autorizado; sin plano de implantación de servicios","sourceScope":"Decisiones gráficas de modelado, no especificación del fabricante ni diseño técnico de instalaciones."}; IncluirEnMediciones: no; Criterio: {"enabled":true,"userRequestedProvisional3D":true,"basis":"Propuesta aproximada de colocación en zonas libres junto a viales, autorizada para visualización.","status":"illustrative_not_documented","physicalHeightConfirmed":false,"quantityEligible":false,"notForConstruction":true,"warning":"Ubicación y dimensiones provisionales; no acredita cobertura contra incendios ni cálculo lumínico. Esquema de coordinación, no apto para construcción, compra ni mediciones."}
Name | dimensions | visualizationIdentity | positioning = PosicionYEstado = Posicion | geometryMetrics | placementEvidence | Ubicación | Identificador | DimensionesSupuestas
Luminaria LED L01 · provisional | {"documented":[],"assumed":[{"label":"Altura total ilustrativa sobre el terreno","value":6.0,"unit":"m","status":"supuesto","source":"JH-SITE-SERVICES-CONCEPT-20260908"},{"label":"Posición gráfica X local","value":25.0,"unit":"m","status":"supuesto","source":"JH-SITE-SERVICES-CONCEPT-20260908"},{"label":"Posición gráfica Y local","value":95.0,"unit":"m","status":"supuesto","source":"JH-SITE-SERVICES-CONCEPT-20260908"},{"label":"Diámetros gráficos del fuste, inferior / superior","value":"0,17 / 0,09","unit":"m","status":"supuesto","source":"JH-SITE-SERVICES-CONCEPT-20260908"},{"label":"Placa de apoyo gráfica","value":"0,42 × 0,42 × 0,06","unit":"m","status":"supuesto","source":"JH-SITE-SERVICES-CONCEPT-20260908"},{"label":"Carcasa gráfica LED","value":"0,72 × 0,30 × 0,18","unit":"m","status":"supuesto","source":"JH-SITE-SERVICES-CONCEPT-20260908"},{"label":"Vuelo gráfico máximo desde el eje","value":1.4,"unit":"m","status":"supuesto","source":"JH-SITE-SERVICES-CONCEPT-20260908"},{"label":"Brazo y piezas menores","value":"Secciones, inclinación, fijaciones y registro elegidos solo para representación","unit":"","status":"supuesto","source":"JH-SITE-SERVICES-CONCEPT-20260908"}],"geometry":[{"label":"Extensión gráfica en X","value":1.102532,"unit":"m","status":"derivado_del_esquema"},{"label":"Extensión gráfica en Y","value":1.579945,"unit":"m","status":"derivado_del_esquema"},{"label":"Extensión gráfica en Z","value":6.0,"unit":"m","status":"derivado_del_esquema"},{"label":"Cota inferior local de visualización","value":0.783449,"unit":"m","status":"datum_provisional"}],"notes":["Ubicación y dimensiones provisionales; no acredita cobertura contra incendios ni cálculo lumínico. Esquema de coordinación, no apto para construcción, compra ni mediciones."]} | {"elementId":"SITE-LIGHT-01","ifcGuid":"1G_muohzHTcgDJ5bhCDslh","ifcClass":"IfcLightFixture","buildingId":"site","buildingName":"Urbanización y parcela","sourceDocumentId":"JH-SITE-SERVICES-CONCEPT-20260908","sourceRepresentationKind":"conceptualVolume"} | {"Ubicación":"Jardín norte de oficinas","Sistema de coordenadas":"Modelo local en metros; origen horizontal ETRS89 / UTM 29N 729400 / 4301550 m","Base representada (X, Y, Z)":[25.0,95.0,0.783449],"Superficie de apoyo":"site_002","Criterio de cota":"Interpolación sobre triángulos del jardín ya representado; datum absoluto pendiente de confirmación.","Orientación":"Brazo o cara principal orientado hacia el borde de vial más próximo, solo para visualización.","Separación gráfica al vial (m)":0.786063,"Elemento existente próximo":"office_0257","Separación gráfica al elemento (m)":2.561195} | {"boundingBoxM":{"min":[24.714051,94.714051,0.783449],"max":[25.816583,96.293996,6.783449]},"extentsM":[1.102532,1.579945,6.0],"meshSurfaceM2":4.343932,"meshVolumeM3":0.134891,"closedSolid":true,"basis":"Esquema provisional de coordinación autorizado por el cliente. Tuberías, soportes, alumbrado e hidrantes con dimensiones y posiciones orientativas; no para construcción ni cómputo de cantidades."} | {"location":"Jardín norte de oficinas","coordinateSystem":"Modelo local en metros; origen horizontal ETRS89 / UTM 29N 729400 / 4301550 m","modelBaseM":[25.0,95.0,0.783449],"groundObjectId":"site_002","groundBasis":"Interpolación sobre triángulos del jardín ya representado; datum absoluto pendiente de confirmación.","orientationBasis":"Brazo o cara principal orientado hacia el borde de vial más próximo, solo para visualización.","roadClearanceOfGraphicFootprintM":0.786063,"nearestExistingObjectId":"office_0257","graphicClearanceToNearestExistingObjectM":2.561195} | Jardín norte de oficinas | SITE-LIGHT-01 | [{"label":"Altura total ilustrativa sobre el terreno","value":6.0,"unit":"m","status":"supuesto","source":"JH-SITE-SERVICES-CONCEPT-20260908"},{"label":"Posición gráfica X local","value":25.0,"unit":"m","status":"supuesto","source":"JH-SITE-SERVICES-CONCEPT-20260908"},{"label":"Posición gráfica Y local","value":95.0,"unit":"m","status":"supuesto","source":"JH-SITE-SERVICES-CONCEPT-20260908"},{"label":"Diámetros gráficos del fuste, inferior / superior","value":"0,17 / 0,09","unit":"m","status":"supuesto","source":"JH-SITE-SERVICES-CONCEPT-20260908"},{"label":"Placa de apoyo gráfica","value":"0,42 × 0,42 × 0,06","unit":"m","status":"supuesto","source":"JH-SITE-SERVICES-CONCEPT-20260908"},{"label":"Carcasa gráfica LED","value":"0,72 × 0,30 × 0,18","unit":"m","status":"supuesto","source":"JH-SITE-SERVICES-CONCEPT-20260908"},{"label":"Vuelo gráfico máximo desde el eje","value":1.4,"unit":"m","status":"supuesto","source":"JH-SITE-SERVICES-CONCEPT-20260908"},{"label":"Brazo y piezas menores","value":"Secciones, inclinación, fijaciones y registro elegidos solo para representación","unit":"","status":"supuesto","source":"JH-SITE-SERVICES-CONCEPT-20260908"}]
Luminaria LED L02 · provisional | {"documented":[],"assumed":[{"label":"Altura total ilustrativa sobre el terreno","value":6.0,"unit":"m","status":"supuesto","source":"JH-SITE-SERVICES-CONCEPT-20260908"},{"label":"Posición gráfica X local","value":63.0,"unit":"m","status":"supuesto","source":"JH-SITE-SERVICES-CONCEPT-20260908"},{"label":"Posición gráfica Y local","value":90.0,"unit":"m","status":"supuesto","source":"JH-SITE-SERVICES-CONCEPT-20260908"},{"label":"Diámetros gráficos del fuste, inferior / superior","value":"0,17 / 0,09","unit":"m","status":"supuesto","source":"JH-SITE-SERVICES-CONCEPT-20260908"},{"label":"Placa de apoyo gráfica","value":"0,42 × 0,42 × 0,06","unit":"m","status":"supuesto","source":"JH-SITE-SERVICES-CONCEPT-20260908"},{"label":"Carcasa gráfica LED","value":"0,72 × 0,30 × 0,18","unit":"m","status":"supuesto","source":"JH-SITE-SERVICES-CONCEPT-20260908"},{"label":"Vuelo gráfico máximo desde el eje","value":1.4,"unit":"m","status":"supuesto","source":"JH-SITE-SERVICES-CONCEPT-20260908"},{"label":"Brazo y piezas menores","value":"Secciones, inclinación, fijaciones y registro elegidos solo para representación","unit":"","status":"supuesto","source":"JH-SITE-SERVICES-CONCEPT-20260908"}],"geometry":[{"label":"Extensión gráfica en X","value":0.577674,"unit":"m","status":"derivado_del_esquema"},{"label":"Extensión gráfica en Y","value":1.644183,"unit":"m","status":"derivado_del_esquema"},{"label":"Extensión gráfica en Z","value":6.0,"unit":"m","status":"derivado_del_esquema"},{"label":"Cota inferior local de visualización","value":1.441939,"unit":"m","status":"datum_provisional"}],"notes":["Ubicación y dimensiones provisionales; no acredita cobertura contra incendios ni cálculo lumínico. Esquema de coordinación, no apto para construcción, compra ni mediciones."]} | {"elementId":"SITE-LIGHT-02","ifcGuid":"3aVbSpPFrQLQub0Xf3fONk","ifcClass":"IfcLightFixture","buildingId":"site","buildingName":"Urbanización y parcela","sourceDocumentId":"JH-SITE-SERVICES-CONCEPT-20260908","sourceRepresentationKind":"conceptualVolume"} | {"Ubicación":"Borde norte de la zona de equipos","Sistema de coordenadas":"Modelo local en metros; origen horizontal ETRS89 / UTM 29N 729400 / 4301550 m","Base representada (X, Y, Z)":[63.0,90.0,1.441939],"Superficie de apoyo":"site_001","Criterio de cota":"Interpolación sobre triángulos del jardín ya representado; datum absoluto pendiente de confirmación.","Orientación":"Brazo o cara principal orientado hacia el borde de vial más próximo, solo para visualización.","Separación gráfica al vial (m)":1.263742,"Elemento existente próximo":"found_0904_f0afc95ba236c4","Separación gráfica al elemento (m)":6.26618} | {"boundingBoxM":{"min":[62.763152,89.763152,1.441939],"max":[63.340826,91.407335,7.441939]},"extentsM":[0.577674,1.644183,6.0],"meshSurfaceM2":4.343933,"meshVolumeM3":0.134891,"closedSolid":true,"basis":"Esquema provisional de coordinación autorizado por el cliente. Tuberías, soportes, alumbrado e hidrantes con dimensiones y posiciones orientativas; no para construcción ni cómputo de cantidades."} | {"location":"Borde norte de la zona de equipos","coordinateSystem":"Modelo local en metros; origen horizontal ETRS89 / UTM 29N 729400 / 4301550 m","modelBaseM":[63.0,90.0,1.441939],"groundObjectId":"site_001","groundBasis":"Interpolación sobre triángulos del jardín ya representado; datum absoluto pendiente de confirmación.","orientationBasis":"Brazo o cara principal orientado hacia el borde de vial más próximo, solo para visualización.","roadClearanceOfGraphicFootprintM":1.263742,"nearestExistingObjectId":"found_0904_f0afc95ba236c4","graphicClearanceToNearestExistingObjectM":6.26618} | Borde norte de la zona de equipos | SITE-LIGHT-02 | [{"label":"Altura total ilustrativa sobre el terreno","value":6.0,"unit":"m","status":"supuesto","source":"JH-SITE-SERVICES-CONCEPT-20260908"},{"label":"Posición gráfica X local","value":63.0,"unit":"m","status":"supuesto","source":"JH-SITE-SERVICES-CONCEPT-20260908"},{"label":"Posición gráfica Y local","value":90.0,"unit":"m","status":"supuesto","source":"JH-SITE-SERVICES-CONCEPT-20260908"},{"label":"Diámetros gráficos del fuste, inferior / superior","value":"0,17 / 0,09","unit":"m","status":"supuesto","source":"JH-SITE-SERVICES-CONCEPT-20260908"},{"label":"Placa de apoyo gráfica","value":"0,42 × 0,42 × 0,06","unit":"m","status":"supuesto","source":"JH-SITE-SERVICES-CONCEPT-20260908"},{"label":"Carcasa gráfica LED","value":"0,72 × 0,30 × 0,18","unit":"m","status":"supuesto","source":"JH-SITE-SERVICES-CONCEPT-20260908"},{"label":"Vuelo gráfico máximo desde el eje","value":1.4,"unit":"m","status":"supuesto","source":"JH-SITE-SERVICES-CONCEPT-20260908"},{"label":"Brazo y piezas menores","value":"Secciones, inclinación, fijaciones y registro elegidos solo para representación","unit":"","status":"supuesto","source":"JH-SITE-SERVICES-CONCEPT-20260908"}]
Luminaria LED L03 · provisional | {"documented":[],"assumed":[{"label":"Altura total ilustrativa sobre el terreno","value":6.0,"unit":"m","status":"supuesto","source":"JH-SITE-SERVICES-CONCEPT-20260908"},{"label":"Posición gráfica X local","value":111.0,"unit":"m","status":"supuesto","source":"JH-SITE-SERVICES-CONCEPT-20260908"},{"label":"Posición gráfica Y local","value":83.0,"unit":"m","status":"supuesto","source":"JH-SITE-SERVICES-CONCEPT-20260908"},{"label":"Diámetros gráficos del fuste, inferior / superior","value":"0,17 / 0,09","unit":"m","status":"supuesto","source":"JH-SITE-SERVICES-CONCEPT-20260908"},{"label":"Placa de apoyo gráfica","value":"0,42 × 0,42 × 0,06","unit":"m","status":"supuesto","source":"JH-SITE-SERVICES-CONCEPT-20260908"},{"label":"Carcasa gráfica LED","value":"0,72 × 0,30 × 0,18","unit":"m","status":"supuesto","source":"JH-SITE-SERVICES-CONCEPT-20260908"},{"label":"Vuelo gráfico máximo desde el eje","value":1.4,"unit":"m","status":"supuesto","source":"JH-SITE-SERVICES-CONCEPT-20260908"},{"label":"Brazo y piezas menores","value":"Secciones, inclinación, fijaciones y registro elegidos solo para representación","unit":"","status":"supuesto","source":"JH-SITE-SERVICES-CONCEPT-20260908"}],"geometry":[{"label":"Extensión gráfica en X","value":0.575747,"unit":"m","status":"derivado_del_esquema"},{"label":"Extensión gráfica en Y","value":1.644013,"unit":"m","status":"derivado_del_esquema"},{"label":"Extensión gráfica en Z","value":6.0,"unit":"m","status":"derivado_del_esquema"},{"label":"Cota inferior local de visualización","value":2.443495,"unit":"m","status":"datum_provisional"}],"notes":["Ubicación y dimensiones provisionales; no acredita cobertura contra incendios ni cálculo lumínico. Esquema de coordinación, no apto para construcción, compra ni mediciones."]} | {"elementId":"SITE-LIGHT-03","ifcGuid":"3tKfuB4efMcPZjZiaTFI3x","ifcClass":"IfcLightFixture","buildingId":"site","buildingName":"Urbanización y parcela","sourceDocumentId":"JH-SITE-SERVICES-CONCEPT-20260908","sourceRepresentationKind":"conceptualVolume"} | {"Ubicación":"Curva noreste interior","Sistema de coordenadas":"Modelo local en metros; origen horizontal ETRS89 / UTM 29N 729400 / 4301550 m","Base representada (X, Y, Z)":[111.0,83.0,2.443495],"Superficie de apoyo":"site_001","Criterio de cota":"Interpolación sobre triángulos del jardín ya representado; datum absoluto pendiente de confirmación.","Orientación":"Brazo o cara principal orientado hacia el borde de vial más próximo, solo para visualización.","Separación gráfica al vial (m)":1.63172,"Elemento existente próximo":"FENCE-21B1A-1-BASE","Separación gráfica al elemento (m)":9.432458} | {"boundingBoxM":{"min":[110.763376,82.763376,2.443495],"max":[111.339123,84.407389,8.443495]},"extentsM":[0.575747,1.644013,6.0],"meshSurfaceM2":4.343927,"meshVolumeM3":0.13489,"closedSolid":true,"basis":"Esquema provisional de coordinación autorizado por el cliente. Tuberías, soportes, alumbrado e hidrantes con dimensiones y posiciones orientativas; no para construcción ni cómputo de cantidades."} | {"location":"Curva noreste interior","coordinateSystem":"Modelo local en metros; origen horizontal ETRS89 / UTM 29N 729400 / 4301550 m","modelBaseM":[111.0,83.0,2.443495],"groundObjectId":"site_001","groundBasis":"Interpolación sobre triángulos del jardín ya representado; datum absoluto pendiente de confirmación.","orientationBasis":"Brazo o cara principal orientado hacia el borde de vial más próximo, solo para visualización.","roadClearanceOfGraphicFootprintM":1.63172,"nearestExistingObjectId":"FENCE-21B1A-1-BASE","graphicClearanceToNearestExistingObjectM":9.432458} | Curva noreste interior | SITE-LIGHT-03 | [{"label":"Altura total ilustrativa sobre el terreno","value":6.0,"unit":"m","status":"supuesto","source":"JH-SITE-SERVICES-CONCEPT-20260908"},{"label":"Posición gráfica X local","value":111.0,"unit":"m","status":"supuesto","source":"JH-SITE-SERVICES-CONCEPT-20260908"},{"label":"Posición gráfica Y local","value":83.0,"unit":"m","status":"supuesto","source":"JH-SITE-SERVICES-CONCEPT-20260908"},{"label":"Diámetros gráficos del fuste, inferior / superior","value":"0,17 / 0,09","unit":"m","status":"supuesto","source":"JH-SITE-SERVICES-CONCEPT-20260908"},{"label":"Placa de apoyo gráfica","value":"0,42 × 0,42 × 0,06","unit":"m","status":"supuesto","source":"JH-SITE-SERVICES-CONCEPT-20260908"},{"label":"Carcasa gráfica LED","value":"0,72 × 0,30 × 0,18","unit":"m","status":"supuesto","source":"JH-SITE-SERVICES-CONCEPT-20260908"},{"label":"Vuelo gráfico máximo desde el eje","value":1.4,"unit":"m","status":"supuesto","source":"JH-SITE-SERVICES-CONCEPT-20260908"},{"label":"Brazo y piezas menores","value":"Secciones, inclinación, fijaciones y registro elegidos solo para representación","unit":"","status":"supuesto","source":"JH-SITE-SERVICES-CONCEPT-20260908"}]
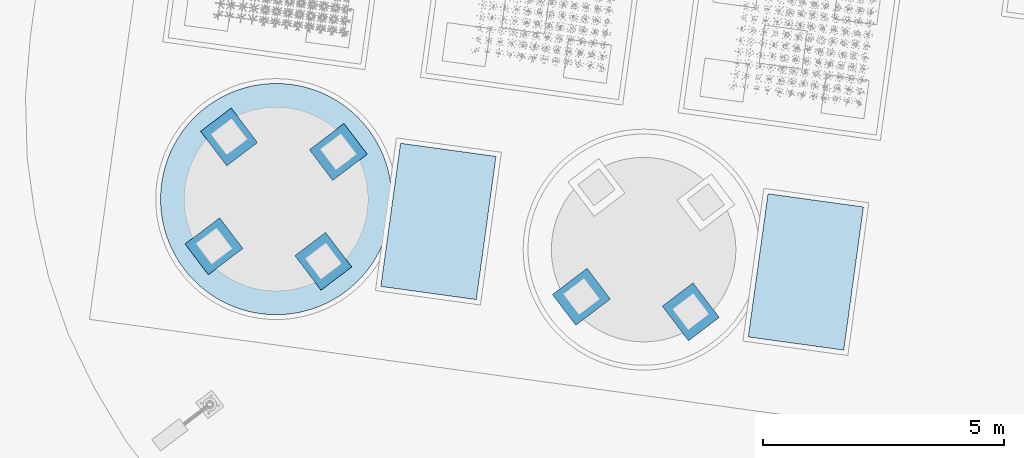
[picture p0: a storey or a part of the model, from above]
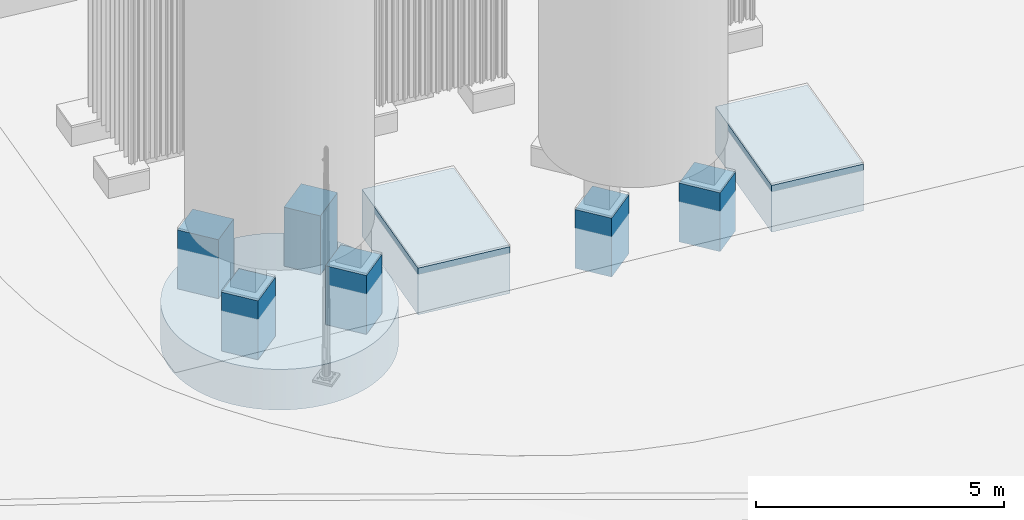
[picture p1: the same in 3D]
Properties of the parts of a building model (IFC4), part 95 of 134

# IfcLightFixture: Luminaria exterior provisional (8)
Name | dimensions | visualizationIdentity | positioning = PosicionYEstado = Posicion | geometryMetrics | placementEvidence | Ubicación | Identificador | DimensionesSupuestas
Luminaria LED L04 · provisional | {"documented":[],"assumed":[{"label":"Altura total ilustrativa sobre el terreno","value":6.0,"unit":"m","status":"supuesto","source":"JH-SITE-SERVICES-CONCEPT-20260908"},{"label":"Posición gráfica X local","value":122.25,"unit":"m","status":"supuesto","source":"JH-SITE-SERVICES-CONCEPT-20260908"},{"label":"Posición gráfica Y local","value":54.0,"unit":"m","status":"supuesto","source":"JH-SITE-SERVICES-CONCEPT-20260908"},{"label":"Diámetros gráficos del fuste, inferior / superior","value":"0,17 / 0,09","unit":"m","status":"supuesto","source":"JH-SITE-SERVICES-CONCEPT-20260908"},{"label":"Placa de apoyo gráfica","value":"0,42 × 0,42 × 0,06","unit":"m","status":"supuesto","source":"JH-SITE-SERVICES-CONCEPT-20260908"},{"label":"Carcasa gráfica LED","value":"0,72 × 0,30 × 0,18","unit":"m","status":"supuesto","source":"JH-SITE-SERVICES-CONCEPT-20260908"},{"label":"Vuelo gráfico máximo desde el eje","value":1.4,"unit":"m","status":"supuesto","source":"JH-SITE-SERVICES-CONCEPT-20260908"},{"label":"Brazo y piezas menores","value":"Secciones, inclinación, fijaciones y registro elegidos solo para representación","unit":"","status":"supuesto","source":"JH-SITE-SERVICES-CONCEPT-20260908"}],"geometry":[{"label":"Extensión gráfica en X","value":1.644118,"unit":"m","status":"derivado_del_esquema"},{"label":"Extensión gráfica en Y","value":0.576924,"unit":"m","status":"derivado_del_esquema"},{"label":"Extensión gráfica en Z","value":6.0,"unit":"m","status":"derivado_del_esquema"},{"label":"Cota inferior local de visualización","value":2.418719,"unit":"m","status":"datum_provisional"}],"notes":["Ubicación y dimensiones provisionales; no acredita cobertura contra incendios ni cálculo lumínico. Esquema de coordinación, no apto para construcción, compra ni mediciones."]} | {"elementId":"SITE-LIGHT-04","ifcGuid":"2gqWjF_dHRxwOB$_1ZRRL9","ifcClass":"IfcLightFixture","buildingId":"site","buildingName":"Urbanización y parcela","sourceDocumentId":"JH-SITE-SERVICES-CONCEPT-20260908","sourceRepresentationKind":"conceptualVolume"} | {"Ubicación":"Borde este interior","Sistema de coordenadas":"Modelo local en metros; origen horizontal ETRS89 / UTM 29N 729400 / 4301550 m","Base representada (X, Y, Z)":[122.25,54.0,2.418719],"Superficie de apoyo":"site_001","Criterio de cota":"Interpolación sobre triángulos del jardín ya representado; datum absoluto pendiente de confirmación.","Orientación":"Brazo o cara principal orientado hacia el borde de vial más próximo, solo para visualización.","Separación gráfica al vial (m)":0.461645,"Elemento existente próximo":"FENCE-21B1A-2-BASE","Separación gráfica al elemento (m)":8.268196} | {"boundingBoxM":{"min":[122.013239,53.659837,2.418719],"max":[123.657357,54.236761,8.418719]},"extentsM":[1.644118,0.576924,6.0],"meshSurfaceM2":4.34393,"meshVolumeM3":0.13489,"closedSolid":true,"basis":"Esquema provisional de coordinación autorizado por el cliente. Tuberías, soportes, alumbrado e hidrantes con dimensiones y posiciones orientativas; no para construcción ni cómputo de cantidades."} | {"location":"Borde este interior","coordinateSystem":"Modelo local en metros; origen horizontal ETRS89 / UTM 29N 729400 / 4301550 m","modelBaseM":[122.25,54.0,2.418719],"groundObjectId":"site_001","groundBasis":"Interpolación sobre triángulos del jardín ya representado; datum absoluto pendiente de confirmación.","orientationBasis":"Brazo o cara principal orientado hacia el borde de vial más próximo, solo para visualización.","roadClearanceOfGraphicFootprintM":0.461645,"nearestExistingObjectId":"FENCE-21B1A-2-BASE","graphicClearanceToNearestExistingObjectM":8.268196} | Borde este interior | SITE-LIGHT-04 | [{"label":"Altura total ilustrativa sobre el terreno","value":6.0,"unit":"m","status":"supuesto","source":"JH-SITE-SERVICES-CONCEPT-20260908"},{"label":"Posición gráfica X local","value":122.25,"unit":"m","status":"supuesto","source":"JH-SITE-SERVICES-CONCEPT-20260908"},{"label":"Posición gráfica Y local","value":54.0,"unit":"m","status":"supuesto","source":"JH-SITE-SERVICES-CONCEPT-20260908"},{"label":"Diámetros gráficos del fuste, inferior / superior","value":"0,17 / 0,09","unit":"m","status":"supuesto","source":"JH-SITE-SERVICES-CONCEPT-20260908"},{"label":"Placa de apoyo gráfica","value":"0,42 × 0,42 × 0,06","unit":"m","status":"supuesto","source":"JH-SITE-SERVICES-CONCEPT-20260908"},{"label":"Carcasa gráfica LED","value":"0,72 × 0,30 × 0,18","unit":"m","status":"supuesto","source":"JH-SITE-SERVICES-CONCEPT-20260908"},{"label":"Vuelo gráfico máximo desde el eje","value":1.4,"unit":"m","status":"supuesto","source":"JH-SITE-SERVICES-CONCEPT-20260908"},{"label":"Brazo y piezas menores","value":"Secciones, inclinación, fijaciones y registro elegidos solo para representación","unit":"","status":"supuesto","source":"JH-SITE-SERVICES-CONCEPT-20260908"}]
Luminaria LED L05 · provisional | {"documented":[],"assumed":[{"label":"Altura total ilustrativa sobre el terreno","value":6.0,"unit":"m","status":"supuesto","source":"JH-SITE-SERVICES-CONCEPT-20260908"},{"label":"Posición gráfica X local","value":114.0,"unit":"m","status":"supuesto","source":"JH-SITE-SERVICES-CONCEPT-20260908"},{"label":"Posición gráfica Y local","value":18.0,"unit":"m","status":"supuesto","source":"JH-SITE-SERVICES-CONCEPT-20260908"},{"label":"Diámetros gráficos del fuste, inferior / superior","value":"0,17 / 0,09","unit":"m","status":"supuesto","source":"JH-SITE-SERVICES-CONCEPT-20260908"},{"label":"Placa de apoyo gráfica","value":"0,42 × 0,42 × 0,06","unit":"m","status":"supuesto","source":"JH-SITE-SERVICES-CONCEPT-20260908"},{"label":"Carcasa gráfica LED","value":"0,72 × 0,30 × 0,18","unit":"m","status":"supuesto","source":"JH-SITE-SERVICES-CONCEPT-20260908"},{"label":"Vuelo gráfico máximo desde el eje","value":1.4,"unit":"m","status":"supuesto","source":"JH-SITE-SERVICES-CONCEPT-20260908"},{"label":"Brazo y piezas menores","value":"Secciones, inclinación, fijaciones y registro elegidos solo para representación","unit":"","status":"supuesto","source":"JH-SITE-SERVICES-CONCEPT-20260908"}],"geometry":[{"label":"Extensión gráfica en X","value":1.264276,"unit":"m","status":"derivado_del_esquema"},{"label":"Extensión gráfica en Y","value":1.497394,"unit":"m","status":"derivado_del_esquema"},{"label":"Extensión gráfica en Z","value":6.0,"unit":"m","status":"derivado_del_esquema"},{"label":"Cota inferior local de visualización","value":1.957707,"unit":"m","status":"datum_provisional"}],"notes":["Ubicación y dimensiones provisionales; no acredita cobertura contra incendios ni cálculo lumínico. Esquema de coordinación, no apto para construcción, compra ni mediciones."]} | {"elementId":"SITE-LIGHT-05","ifcGuid":"3$OjDZRJrP1wxWN4pnAPYk","ifcClass":"IfcLightFixture","buildingId":"site","buildingName":"Urbanización y parcela","sourceDocumentId":"JH-SITE-SERVICES-CONCEPT-20260908","sourceRepresentationKind":"conceptualVolume"} | {"Ubicación":"Curva sureste interior","Sistema de coordenadas":"Modelo local en metros; origen horizontal ETRS89 / UTM 29N 729400 / 4301550 m","Base representada (X, Y, Z)":[114.0,18.0,1.957707],"Superficie de apoyo":"site_001","Criterio de cota":"Interpolación sobre triángulos del jardín ya representado; datum absoluto pendiente de confirmación.","Orientación":"Brazo o cara principal orientado hacia el borde de vial más próximo, solo para visualización.","Separación gráfica al vial (m)":1.172965,"Elemento existente próximo":"FENCE-21B1A-2-BASE","Separación gráfica al elemento (m)":11.825} | {"boundingBoxM":{"min":[113.705609,16.796997,1.957707],"max":[114.969885,18.294391,7.957707]},"extentsM":[1.264276,1.497394,6.0],"meshSurfaceM2":4.343925,"meshVolumeM3":0.13489,"closedSolid":true,"basis":"Esquema provisional de coordinación autorizado por el cliente. Tuberías, soportes, alumbrado e hidrantes con dimensiones y posiciones orientativas; no para construcción ni cómputo de cantidades."} | {"location":"Curva sureste interior","coordinateSystem":"Modelo local en metros; origen horizontal ETRS89 / UTM 29N 729400 / 4301550 m","modelBaseM":[114.0,18.0,1.957707],"groundObjectId":"site_001","groundBasis":"Interpolación sobre triángulos del jardín ya representado; datum absoluto pendiente de confirmación.","orientationBasis":"Brazo o cara principal orientado hacia el borde de vial más próximo, solo para visualización.","roadClearanceOfGraphicFootprintM":1.172965,"nearestExistingObjectId":"FENCE-21B1A-2-BASE","graphicClearanceToNearestExistingObjectM":11.825} | Curva sureste interior | SITE-LIGHT-05 | [{"label":"Altura total ilustrativa sobre el terreno","value":6.0,"unit":"m","status":"supuesto","source":"JH-SITE-SERVICES-CONCEPT-20260908"},{"label":"Posición gráfica X local","value":114.0,"unit":"m","status":"supuesto","source":"JH-SITE-SERVICES-CONCEPT-20260908"},{"label":"Posición gráfica Y local","value":18.0,"unit":"m","status":"supuesto","source":"JH-SITE-SERVICES-CONCEPT-20260908"},{"label":"Diámetros gráficos del fuste, inferior / superior","value":"0,17 / 0,09","unit":"m","status":"supuesto","source":"JH-SITE-SERVICES-CONCEPT-20260908"},{"label":"Placa de apoyo gráfica","value":"0,42 × 0,42 × 0,06","unit":"m","status":"supuesto","source":"JH-SITE-SERVICES-CONCEPT-20260908"},{"label":"Carcasa gráfica LED","value":"0,72 × 0,30 × 0,18","unit":"m","status":"supuesto","source":"JH-SITE-SERVICES-CONCEPT-20260908"},{"label":"Vuelo gráfico máximo desde el eje","value":1.4,"unit":"m","status":"supuesto","source":"JH-SITE-SERVICES-CONCEPT-20260908"},{"label":"Brazo y piezas menores","value":"Secciones, inclinación, fijaciones y registro elegidos solo para representación","unit":"","status":"supuesto","source":"JH-SITE-SERVICES-CONCEPT-20260908"}]
Luminaria LED L06 · provisional | {"documented":[],"assumed":[{"label":"Altura total ilustrativa sobre el terreno","value":6.0,"unit":"m","status":"supuesto","source":"JH-SITE-SERVICES-CONCEPT-20260908"},{"label":"Posición gráfica X local","value":75.0,"unit":"m","status":"supuesto","source":"JH-SITE-SERVICES-CONCEPT-20260908"},{"label":"Posición gráfica Y local","value":21.0,"unit":"m","status":"supuesto","source":"JH-SITE-SERVICES-CONCEPT-20260908"},{"label":"Diámetros gráficos del fuste, inferior / superior","value":"0,17 / 0,09","unit":"m","status":"supuesto","source":"JH-SITE-SERVICES-CONCEPT-20260908"},{"label":"Placa de apoyo gráfica","value":"0,42 × 0,42 × 0,06","unit":"m","status":"supuesto","source":"JH-SITE-SERVICES-CONCEPT-20260908"},{"label":"Carcasa gráfica LED","value":"0,72 × 0,30 × 0,18","unit":"m","status":"supuesto","source":"JH-SITE-SERVICES-CONCEPT-20260908"},{"label":"Vuelo gráfico máximo desde el eje","value":1.4,"unit":"m","status":"supuesto","source":"JH-SITE-SERVICES-CONCEPT-20260908"},{"label":"Brazo y piezas menores","value":"Secciones, inclinación, fijaciones y registro elegidos solo para representación","unit":"","status":"supuesto","source":"JH-SITE-SERVICES-CONCEPT-20260908"}],"geometry":[{"label":"Extensión gráfica en X","value":0.576371,"unit":"m","status":"derivado_del_esquema"},{"label":"Extensión gráfica en Y","value":1.644069,"unit":"m","status":"derivado_del_esquema"},{"label":"Extensión gráfica en Z","value":6.0,"unit":"m","status":"derivado_del_esquema"},{"label":"Cota inferior local de visualización","value":1.580865,"unit":"m","status":"datum_provisional"}],"notes":["Ubicación y dimensiones provisionales; no acredita cobertura contra incendios ni cálculo lumínico. Esquema de coordinación, no apto para construcción, compra ni mediciones."]} | {"elementId":"SITE-LIGHT-06","ifcGuid":"3hjWVsHYXJ7grzoTmFiNNj","ifcClass":"IfcLightFixture","buildingId":"site","buildingName":"Urbanización y parcela","sourceDocumentId":"JH-SITE-SERVICES-CONCEPT-20260908","sourceRepresentationKind":"conceptualVolume"} | {"Ubicación":"Borde sur interior","Sistema de coordenadas":"Modelo local en metros; origen horizontal ETRS89 / UTM 29N 729400 / 4301550 m","Base representada (X, Y, Z)":[75.0,21.0,1.580865],"Superficie de apoyo":"site_001","Criterio de cota":"Interpolación sobre triángulos del jardín ya representado; datum absoluto pendiente de confirmación.","Orientación":"Brazo o cara principal orientado hacia el borde de vial más próximo, solo para visualización.","Separación gráfica al vial (m)":1.798325,"Elemento existente próximo":"FENCE-21B33-1-BASE","Separación gráfica al elemento (m)":9.707071} | {"boundingBoxM":{"min":[74.660326,19.592628,1.580865],"max":[75.236697,21.236697,7.580865]},"extentsM":[0.576371,1.644069,6.0],"meshSurfaceM2":4.343929,"meshVolumeM3":0.134891,"closedSolid":true,"basis":"Esquema provisional de coordinación autorizado por el cliente. Tuberías, soportes, alumbrado e hidrantes con dimensiones y posiciones orientativas; no para construcción ni cómputo de cantidades."} | {"location":"Borde sur interior","coordinateSystem":"Modelo local en metros; origen horizontal ETRS89 / UTM 29N 729400 / 4301550 m","modelBaseM":[75.0,21.0,1.580865],"groundObjectId":"site_001","groundBasis":"Interpolación sobre triángulos del jardín ya representado; datum absoluto pendiente de confirmación.","orientationBasis":"Brazo o cara principal orientado hacia el borde de vial más próximo, solo para visualización.","roadClearanceOfGraphicFootprintM":1.798325,"nearestExistingObjectId":"FENCE-21B33-1-BASE","graphicClearanceToNearestExistingObjectM":9.707071} | Borde sur interior | SITE-LIGHT-06 | [{"label":"Altura total ilustrativa sobre el terreno","value":6.0,"unit":"m","status":"supuesto","source":"JH-SITE-SERVICES-CONCEPT-20260908"},{"label":"Posición gráfica X local","value":75.0,"unit":"m","status":"supuesto","source":"JH-SITE-SERVICES-CONCEPT-20260908"},{"label":"Posición gráfica Y local","value":21.0,"unit":"m","status":"supuesto","source":"JH-SITE-SERVICES-CONCEPT-20260908"},{"label":"Diámetros gráficos del fuste, inferior / superior","value":"0,17 / 0,09","unit":"m","status":"supuesto","source":"JH-SITE-SERVICES-CONCEPT-20260908"},{"label":"Placa de apoyo gráfica","value":"0,42 × 0,42 × 0,06","unit":"m","status":"supuesto","source":"JH-SITE-SERVICES-CONCEPT-20260908"},{"label":"Carcasa gráfica LED","value":"0,72 × 0,30 × 0,18","unit":"m","status":"supuesto","source":"JH-SITE-SERVICES-CONCEPT-20260908"},{"label":"Vuelo gráfico máximo desde el eje","value":1.4,"unit":"m","status":"supuesto","source":"JH-SITE-SERVICES-CONCEPT-20260908"},{"label":"Brazo y piezas menores","value":"Secciones, inclinación, fijaciones y registro elegidos solo para representación","unit":"","status":"supuesto","source":"JH-SITE-SERVICES-CONCEPT-20260908"}]
Luminaria LED L07 · provisional | {"documented":[],"assumed":[{"label":"Altura total ilustrativa sobre el terreno","value":6.0,"unit":"m","status":"supuesto","source":"JH-SITE-SERVICES-CONCEPT-20260908"},{"label":"Posición gráfica X local","value":35.0,"unit":"m","status":"supuesto","source":"JH-SITE-SERVICES-CONCEPT-20260908"},{"label":"Posición gráfica Y local","value":28.25,"unit":"m","status":"supuesto","source":"JH-SITE-SERVICES-CONCEPT-20260908"},{"label":"Diámetros gráficos del fuste, inferior / superior","value":"0,17 / 0,09","unit":"m","status":"supuesto","source":"JH-SITE-SERVICES-CONCEPT-20260908"},{"label":"Placa de apoyo gráfica","value":"0,42 × 0,42 × 0,06","unit":"m","status":"supuesto","source":"JH-SITE-SERVICES-CONCEPT-20260908"},{"label":"Carcasa gráfica LED","value":"0,72 × 0,30 × 0,18","unit":"m","status":"supuesto","source":"JH-SITE-SERVICES-CONCEPT-20260908"},{"label":"Vuelo gráfico máximo desde el eje","value":1.4,"unit":"m","status":"supuesto","source":"JH-SITE-SERVICES-CONCEPT-20260908"},{"label":"Brazo y piezas menores","value":"Secciones, inclinación, fijaciones y registro elegidos solo para representación","unit":"","status":"supuesto","source":"JH-SITE-SERVICES-CONCEPT-20260908"}],"geometry":[{"label":"Extensión gráfica en X","value":1.499764,"unit":"m","status":"derivado_del_esquema"},{"label":"Extensión gráfica en Y","value":1.260627,"unit":"m","status":"derivado_del_esquema"},{"label":"Extensión gráfica en Z","value":6.0,"unit":"m","status":"derivado_del_esquema"},{"label":"Cota inferior local de visualización","value":1.248029,"unit":"m","status":"datum_provisional"}],"notes":["Ubicación y dimensiones provisionales; no acredita cobertura contra incendios ni cálculo lumínico. Esquema de coordinación, no apto para construcción, compra ni mediciones."]} | {"elementId":"SITE-LIGHT-07","ifcGuid":"0Mys9tRtvPDw_2KlebmamR","ifcClass":"IfcLightFixture","buildingId":"site","buildingName":"Urbanización y parcela","sourceDocumentId":"JH-SITE-SERVICES-CONCEPT-20260908","sourceRepresentationKind":"conceptualVolume"} | {"Ubicación":"Entorno suroeste de equipos","Sistema de coordenadas":"Modelo local en metros; origen horizontal ETRS89 / UTM 29N 729400 / 4301550 m","Base representada (X, Y, Z)":[35.0,28.25,1.248029],"Superficie de apoyo":"site_001","Criterio de cota":"Interpolación sobre triángulos del jardín ya representado; datum absoluto pendiente de confirmación.","Orientación":"Brazo o cara principal orientado hacia el borde de vial más próximo, solo para visualización.","Separación gráfica al vial (m)":0.444935,"Elemento existente próximo":"found_0904_05e45d36ea4f96","Separación gráfica al elemento (m)":1.688986} | {"boundingBoxM":{"min":[33.794491,27.283628,1.248029],"max":[35.294255,28.544255,7.248029]},"extentsM":[1.499764,1.260627,6.0],"meshSurfaceM2":4.343931,"meshVolumeM3":0.134891,"closedSolid":true,"basis":"Esquema provisional de coordinación autorizado por el cliente. Tuberías, soportes, alumbrado e hidrantes con dimensiones y posiciones orientativas; no para construcción ni cómputo de cantidades."} | {"location":"Entorno suroeste de equipos","coordinateSystem":"Modelo local en metros; origen horizontal ETRS89 / UTM 29N 729400 / 4301550 m","modelBaseM":[35.0,28.25,1.248029],"groundObjectId":"site_001","groundBasis":"Interpolación sobre triángulos del jardín ya representado; datum absoluto pendiente de confirmación.","orientationBasis":"Brazo o cara principal orientado hacia el borde de vial más próximo, solo para visualización.","roadClearanceOfGraphicFootprintM":0.444935,"nearestExistingObjectId":"found_0904_05e45d36ea4f96","graphicClearanceToNearestExistingObjectM":1.688986} | Entorno suroeste de equipos | SITE-LIGHT-07 | [{"label":"Altura total ilustrativa sobre el terreno","value":6.0,"unit":"m","status":"supuesto","source":"JH-SITE-SERVICES-CONCEPT-20260908"},{"label":"Posición gráfica X local","value":35.0,"unit":"m","status":"supuesto","source":"JH-SITE-SERVICES-CONCEPT-20260908"},{"label":"Posición gráfica Y local","value":28.25,"unit":"m","status":"supuesto","source":"JH-SITE-SERVICES-CONCEPT-20260908"},{"label":"Diámetros gráficos del fuste, inferior / superior","value":"0,17 / 0,09","unit":"m","status":"supuesto","source":"JH-SITE-SERVICES-CONCEPT-20260908"},{"label":"Placa de apoyo gráfica","value":"0,42 × 0,42 × 0,06","unit":"m","status":"supuesto","source":"JH-SITE-SERVICES-CONCEPT-20260908"},{"label":"Carcasa gráfica LED","value":"0,72 × 0,30 × 0,18","unit":"m","status":"supuesto","source":"JH-SITE-SERVICES-CONCEPT-20260908"},{"label":"Vuelo gráfico máximo desde el eje","value":1.4,"unit":"m","status":"supuesto","source":"JH-SITE-SERVICES-CONCEPT-20260908"},{"label":"Brazo y piezas menores","value":"Secciones, inclinación, fijaciones y registro elegidos solo para representación","unit":"","status":"supuesto","source":"JH-SITE-SERVICES-CONCEPT-20260908"}]
Luminaria LED L08 · provisional | {"documented":[],"assumed":[{"label":"Altura total ilustrativa sobre el terreno","value":6.0,"unit":"m","status":"supuesto","source":"JH-SITE-SERVICES-CONCEPT-20260908"},{"label":"Posición gráfica X local","value":26.0,"unit":"m","status":"supuesto","source":"JH-SITE-SERVICES-CONCEPT-20260908"},{"label":"Posición gráfica Y local","value":57.0,"unit":"m","status":"supuesto","source":"JH-SITE-SERVICES-CONCEPT-20260908"},{"label":"Diámetros gráficos del fuste, inferior / superior","value":"0,17 / 0,09","unit":"m","status":"supuesto","source":"JH-SITE-SERVICES-CONCEPT-20260908"},{"label":"Placa de apoyo gráfica","value":"0,42 × 0,42 × 0,06","unit":"m","status":"supuesto","source":"JH-SITE-SERVICES-CONCEPT-20260908"},{"label":"Carcasa gráfica LED","value":"0,72 × 0,30 × 0,18","unit":"m","status":"supuesto","source":"JH-SITE-SERVICES-CONCEPT-20260908"},{"label":"Vuelo gráfico máximo desde el eje","value":1.4,"unit":"m","status":"supuesto","source":"JH-SITE-SERVICES-CONCEPT-20260908"},{"label":"Brazo y piezas menores","value":"Secciones, inclinación, fijaciones y registro elegidos solo para representación","unit":"","status":"supuesto","source":"JH-SITE-SERVICES-CONCEPT-20260908"}],"geometry":[{"label":"Extensión gráfica en X","value":1.644065,"unit":"m","status":"derivado_del_esquema"},{"label":"Extensión gráfica en Y","value":0.576331,"unit":"m","status":"derivado_del_esquema"},{"label":"Extensión gráfica en Z","value":6.0,"unit":"m","status":"derivado_del_esquema"},{"label":"Cota inferior local de visualización","value":0.938896,"unit":"m","status":"datum_provisional"}],"notes":["Ubicación y dimensiones provisionales; no acredita cobertura contra incendios ni cálculo lumínico. Esquema de coordinación, no apto para construcción, compra ni mediciones."]} | {"elementId":"SITE-LIGHT-08","ifcGuid":"0F7zTUYkDKa87fRPUkOaHG","ifcClass":"IfcLightFixture","buildingId":"site","buildingName":"Urbanización y parcela","sourceDocumentId":"JH-SITE-SERVICES-CONCEPT-20260908","sourceRepresentationKind":"conceptualVolume"} | {"Ubicación":"Jardín oeste junto al vial","Sistema de coordenadas":"Modelo local en metros; origen horizontal ETRS89 / UTM 29N 729400 / 4301550 m","Base representada (X, Y, Z)":[26.0,57.0,0.938896],"Superficie de apoyo":"site_002","Criterio de cota":"Interpolación sobre triángulos del jardín ya representado; datum absoluto pendiente de confirmación.","Orientación":"Brazo o cara principal orientado hacia el borde de vial más próximo, solo para visualización.","Separación gráfica al vial (m)":0.735424,"Elemento existente próximo":"found_0904_4a62e3ef3a2717","Separación gráfica al elemento (m)":8.665327} | {"boundingBoxM":{"min":[25.763308,56.660361,0.938896],"max":[27.407373,57.236692,6.938896]},"extentsM":[1.644065,0.576331,6.0],"meshSurfaceM2":4.343933,"meshVolumeM3":0.134891,"closedSolid":true,"basis":"Esquema provisional de coordinación autorizado por el cliente. Tuberías, soportes, alumbrado e hidrantes con dimensiones y posiciones orientativas; no para construcción ni cómputo de cantidades."} | {"location":"Jardín oeste junto al vial","coordinateSystem":"Modelo local en metros; origen horizontal ETRS89 / UTM 29N 729400 / 4301550 m","modelBaseM":[26.0,57.0,0.938896],"groundObjectId":"site_002","groundBasis":"Interpolación sobre triángulos del jardín ya representado; datum absoluto pendiente de confirmación.","orientationBasis":"Brazo o cara principal orientado hacia el borde de vial más próximo, solo para visualización.","roadClearanceOfGraphicFootprintM":0.735424,"nearestExistingObjectId":"found_0904_4a62e3ef3a2717","graphicClearanceToNearestExistingObjectM":8.665327} | Jardín oeste junto al vial | SITE-LIGHT-08 | [{"label":"Altura total ilustrativa sobre el terreno","value":6.0,"unit":"m","status":"supuesto","source":"JH-SITE-SERVICES-CONCEPT-20260908"},{"label":"Posición gráfica X local","value":26.0,"unit":"m","status":"supuesto","source":"JH-SITE-SERVICES-CONCEPT-20260908"},{"label":"Posición gráfica Y local","value":57.0,"unit":"m","status":"supuesto","source":"JH-SITE-SERVICES-CONCEPT-20260908"},{"label":"Diámetros gráficos del fuste, inferior / superior","value":"0,17 / 0,09","unit":"m","status":"supuesto","source":"JH-SITE-SERVICES-CONCEPT-20260908"},{"label":"Placa de apoyo gráfica","value":"0,42 × 0,42 × 0,06","unit":"m","status":"supuesto","source":"JH-SITE-SERVICES-CONCEPT-20260908"},{"label":"Carcasa gráfica LED","value":"0,72 × 0,30 × 0,18","unit":"m","status":"supuesto","source":"JH-SITE-SERVICES-CONCEPT-20260908"},{"label":"Vuelo gráfico máximo desde el eje","value":1.4,"unit":"m","status":"supuesto","source":"JH-SITE-SERVICES-CONCEPT-20260908"},{"label":"Brazo y piezas menores","value":"Secciones, inclinación, fijaciones y registro elegidos solo para representación","unit":"","status":"supuesto","source":"JH-SITE-SERVICES-CONCEPT-20260908"}]

# IfcMember (16)
In: Parcela industrial Jinhong
Document: Soportes de equipos SL1201 y SL401/402; Planta de estructuras metálicas; Cimentaciones de equipos y pedestales del fabricante · revisión recibida 04/09/2026; Group: BIM · Equipos; SL1201 · estructura de soporte según planos
JH_InformacionBIM - buildingId: process_plant; buildingName: Planta de proceso; category: Estructura portante de equipo SL1201; ifcClass: IfcMember; material: {"name":"Acero Q235B","status":"documented","source":"GD05001, lámina 1 · lista de materiales"}; source: {"documentId":"SOPC-PROCESS_020","title":"GD05001 · soporte SL1201","sheet":"1 de 2","date":"2026-05","revision":"00","dateBasis":"Cajetín de plano; recibido nuevamente el 09/09/2026"}; status: derived; representationKind: equipmentSupport; heightStatus: documented_relative; physicalHeightConfirmed: yes; quantityEligible: no; assemblyId: SL1201; issues: ["Acabado, soldaduras, tornillos y detalles de unión no representados.","El datum absoluto 286,10 m sigue siendo provisional."]; layerId: equipment; visualLayer: {"id":"equipment","name":"Equipos"}; classification: {"layerId":"equipment","layerName":"Equipos","role":"Soporte SL1201"}; appearance: {"profileId":"support_sl1201_q235b","name":"SL1201 · acero estructural","status":"acabado_visual_provisional","basis":"Tono de coordinación; grado Q235B documentado, pintura final no confirmada"}; componentSeparation: {"status":"barra_independiente"}; supplementaryDrawingReview: {"fecha":"2026-09-09","estado":"Geometría incorporada y cotejada con cuatro apoyos","documentos":["SOPC-PROCESS_019","SOPC-PROCESS_020","LHD2609-JG00100-20260904"],"criterio":"Se conserva la cimentación más reciente; no se sustituye por el plano antiguo.","conclusiones":["Cuatro ejes separados 1,750 m; apoyo +0,200 m; coronación +5,550 m.","Travesaños intermedios con ejes a +2,075 y +3,875 m, derivados de aristas y ejes CAD."]}
JH_Trazabilidad - Capa BIM: Equipos; Conjunto: SL1201; Material: Q235B; Fuente: GD05001, lámina 1; GD05000; cimentaciones 04/09; Categoria: Estructura portante de equipo SL1201; ClaseIFC: IfcMember; EstadoDeInformacion: derived; DocumentoFuente: {"documentId":"SOPC-PROCESS_020","title":"GD05001 · soporte SL1201","sheet":"1 de 2","date":"2026-05","revision":"00","dateBasis":"Cajetín de plano; recibido nuevamente el 09/09/2026"}; IncidenciasPendientes: ["Acabado, soldaduras, tornillos y detalles de unión no representados.","El datum absoluto 286,10 m sigue siendo provisional."]; UsoDeLasMagnitudes: Geometría de coordinación basada en planos recibidos; no sustituye el modelo de fabricación ni una medición certificada. Datum absoluto de proceso provisional.
JH_EvidenciaDeMaterial - name: Acero Q235B; status: documented; source: GD05001, lámina 1 · lista de materiales
JH_DimensionesDocumentadas - Cota inferior del apoyo: 0.2 m; Cota superior del conjunto: 5.55 m; Distancia entre ejes de columnas: 1.75 m
JH_CapaBIM - IdentificadorCapa: equipment; NombreCapa: Equipos; VisibilidadInicial: yes
JH_AcabadoVisual - id: support_sl1201_q235b; name: SL1201 · acero estructural; materialName: Acero Q235B; color: [0.43,0.49,0.54]; colorHex: #6e7d8a; roughness: 0.65; metalness: 0.45; opacity: 1; transparent: no; textureType: none; status: acabado_visual_provisional; appearanceStatus: acabado_visual_provisional; appearanceBasis: Tono de coordinación; grado Q235B documentado, pintura final no confirmada; appearanceReferences: []; physicalMaterialSource: GD05001, lámina 1, lista de materiales Q235B
Name | dimensions | positioning = PosicionYEstado | foundationIds | geometryMetrics | visualizationIdentity | Identificador | Sección exterior (m) = Sección exterior del tubo cuadrado (m) | Espesor (m) = Espesor de pared (m)
SL1201 · columna 1 · tubo 150×150×6 mm | {"documented":[{"label":"Sección exterior del tubo cuadrado","value":0.15,"unit":"m","status":"documentado_o_derivado_del_CAD","source":"GD05001, lámina 1; GD05000; cimentaciones 04/09"},{"label":"Espesor de pared","value":0.006,"unit":"m","status":"documentado_o_derivado_del_CAD","source":"GD05001, lámina 1; GD05000; cimentaciones 04/09"},{"label":"Cota inferior del apoyo","value":0.2,"unit":"m","status":"documentado_o_derivado_del_CAD","source":"GD05001, lámina 1; GD05000; cimentaciones 04/09"},{"label":"Cota superior del conjunto","value":5.55,"unit":"m","status":"documentado_o_derivado_del_CAD","source":"GD05001, lámina 1; GD05000; cimentaciones 04/09"},{"label":"Distancia entre ejes de columnas","value":1.75,"unit":"m","status":"documentado_o_derivado_del_CAD","source":"GD05001, lámina 1; GD05000; cimentaciones 04/09"}],"geometry":[{"label":"Extensión de malla X","value":0.16903271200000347,"unit":"m","status":"documentado_o_derivado_del_CAD","source":"GD05001, lámina 1; GD05000; cimentaciones 04/09"},{"label":"Extensión de malla Y","value":0.16903271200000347,"unit":"m","status":"documentado_o_derivado_del_CAD","source":"GD05001, lámina 1; GD05000; cimentaciones 04/09"},{"label":"Extensión de malla Z","value":5.3500000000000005,"unit":"m","status":"documentado_o_derivado_del_CAD","source":"GD05001, lámina 1; GD05000; cimentaciones 04/09"}],"notes":["Geometría de coordinación basada en planos recibidos; no sustituye el modelo de fabricación ni una medición certificada. Datum absoluto de proceso provisional."]} | {"axisStartManufacturerM":[24.925,24.325,0.2],"axisEndManufacturerM":[24.925,24.325,5.55],"assemblyReferenceENM":[24.925,24.325],"absoluteDatumConfirmed":false,"processZeroAbsoluteM":286.1,"basis":"Posición y cotas relativas contrastadas con C25–C28. Extremos de barras ajustados a caras para coordinación; uniones y soldaduras no representadas."} | ["found_0904_1b4f8e545510b9"] | {"boundingBoxM":{"min":[60.422353,50.637603,1.3],"max":[60.591386,50.806636,6.65]},"extentsM":[0.169033,0.169033,5.35],"meshSurfaceM2":6.426912,"meshVolumeM3":0.01849,"closedSolid":true,"basis":"Geometría de coordinación basada en planos recibidos; no sustituye el modelo de fabricación ni una medición certificada. Datum absoluto de proceso provisional."} | {"elementId":"SL1201-COL-01","ifcGuid":"2IYSWqPFbTKfP4iJJJGOmb","ifcClass":"IfcMember","sourceDocumentId":"SOPC-PROCESS_020"} | SL1201-COL-01 | 0.15 | 0.006
SL1201 · columna 2 · tubo 150×150×6 mm | {"documented":[{"label":"Sección exterior del tubo cuadrado","value":0.15,"unit":"m","status":"documentado_o_derivado_del_CAD","source":"GD05001, lámina 1; GD05000; cimentaciones 04/09"},{"label":"Espesor de pared","value":0.006,"unit":"m","status":"documentado_o_derivado_del_CAD","source":"GD05001, lámina 1; GD05000; cimentaciones 04/09"},{"label":"Cota inferior del apoyo","value":0.2,"unit":"m","status":"documentado_o_derivado_del_CAD","source":"GD05001, lámina 1; GD05000; cimentaciones 04/09"},{"label":"Cota superior del conjunto","value":5.55,"unit":"m","status":"documentado_o_derivado_del_CAD","source":"GD05001, lámina 1; GD05000; cimentaciones 04/09"},{"label":"Distancia entre ejes de columnas","value":1.75,"unit":"m","status":"documentado_o_derivado_del_CAD","source":"GD05001, lámina 1; GD05000; cimentaciones 04/09"}],"geometry":[{"label":"Extensión de malla X","value":0.16903271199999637,"unit":"m","status":"documentado_o_derivado_del_CAD","source":"GD05001, lámina 1; GD05000; cimentaciones 04/09"},{"label":"Extensión de malla Y","value":0.16903271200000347,"unit":"m","status":"documentado_o_derivado_del_CAD","source":"GD05001, lámina 1; GD05000; cimentaciones 04/09"},{"label":"Extensión de malla Z","value":5.3500000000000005,"unit":"m","status":"documentado_o_derivado_del_CAD","source":"GD05001, lámina 1; GD05000; cimentaciones 04/09"}],"notes":["Geometría de coordinación basada en planos recibidos; no sustituye el modelo de fabricación ni una medición certificada. Datum absoluto de proceso provisional."]} | {"axisStartManufacturerM":[26.675,24.325,0.2],"axisEndManufacturerM":[26.675,24.325,5.55],"assemblyReferenceENM":[24.925,24.325],"absoluteDatumConfirmed":false,"processZeroAbsoluteM":286.1,"basis":"Posición y cotas relativas contrastadas con C25–C28. Extremos de barras ajustados a caras para coordinación; uniones y soldaduras no representadas."} | ["found_0904_2eb1daa04dbdce"] | {"boundingBoxM":{"min":[62.156044,50.399246,1.3],"max":[62.325077,50.568279,6.65]},"extentsM":[0.169033,0.169033,5.35],"meshSurfaceM2":6.426912,"meshVolumeM3":0.01849,"closedSolid":true,"basis":"Geometría de coordinación basada en planos recibidos; no sustituye el modelo de fabricación ni una medición certificada. Datum absoluto de proceso provisional."} | {"elementId":"SL1201-COL-02","ifcGuid":"1BMR_UjRfOMQYmXY9AnJyX","ifcClass":"IfcMember","sourceDocumentId":"SOPC-PROCESS_020"} | SL1201-COL-02 | 0.15 | 0.006
SL1201 · columna 3 · tubo 150×150×6 mm | {"documented":[{"label":"Sección exterior del tubo cuadrado","value":0.15,"unit":"m","status":"documentado_o_derivado_del_CAD","source":"GD05001, lámina 1; GD05000; cimentaciones 04/09"},{"label":"Espesor de pared","value":0.006,"unit":"m","status":"documentado_o_derivado_del_CAD","source":"GD05001, lámina 1; GD05000; cimentaciones 04/09"},{"label":"Cota inferior del apoyo","value":0.2,"unit":"m","status":"documentado_o_derivado_del_CAD","source":"GD05001, lámina 1; GD05000; cimentaciones 04/09"},{"label":"Cota superior del conjunto","value":5.55,"unit":"m","status":"documentado_o_derivado_del_CAD","source":"GD05001, lámina 1; GD05000; cimentaciones 04/09"},{"label":"Distancia entre ejes de columnas","value":1.75,"unit":"m","status":"documentado_o_derivado_del_CAD","source":"GD05001, lámina 1; GD05000; cimentaciones 04/09"}],"geometry":[{"label":"Extensión de malla X","value":0.16903271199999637,"unit":"m","status":"documentado_o_derivado_del_CAD","source":"GD05001, lámina 1; GD05000; cimentaciones 04/09"},{"label":"Extensión de malla Y","value":0.16903271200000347,"unit":"m","status":"documentado_o_derivado_del_CAD","source":"GD05001, lámina 1; GD05000; cimentaciones 04/09"},{"label":"Extensión de malla Z","value":5.3500000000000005,"unit":"m","status":"documentado_o_derivado_del_CAD","source":"GD05001, lámina 1; GD05000; cimentaciones 04/09"}],"notes":["Geometría de coordinación basada en planos recibidos; no sustituye el modelo de fabricación ni una medición certificada. Datum absoluto de proceso provisional."]} | {"axisStartManufacturerM":[26.675,26.075,0.2],"axisEndManufacturerM":[26.675,26.075,5.55],"assemblyReferenceENM":[24.925,24.325],"absoluteDatumConfirmed":false,"processZeroAbsoluteM":286.1,"basis":"Posición y cotas relativas contrastadas con C25–C28. Extremos de barras ajustados a caras para coordinación; uniones y soldaduras no representadas."} | ["found_0904_b2ac6c4a33bf3e"] | {"boundingBoxM":{"min":[62.394401,52.132938,1.3],"max":[62.563434,52.301971,6.65]},"extentsM":[0.169033,0.169033,5.35],"meshSurfaceM2":6.426912,"meshVolumeM3":0.01849,"closedSolid":true,"basis":"Geometría de coordinación basada en planos recibidos; no sustituye el modelo de fabricación ni una medición certificada. Datum absoluto de proceso provisional."} | {"elementId":"SL1201-COL-03","ifcGuid":"0Gw11t4WjJ1PvCG8Ekgs2x","ifcClass":"IfcMember","sourceDocumentId":"SOPC-PROCESS_020"} | SL1201-COL-03 | 0.15 | 0.006
SL1201 · columna 4 · tubo 150×150×6 mm | {"documented":[{"label":"Sección exterior del tubo cuadrado","value":0.15,"unit":"m","status":"documentado_o_derivado_del_CAD","source":"GD05001, lámina 1; GD05000; cimentaciones 04/09"},{"label":"Espesor de pared","value":0.006,"unit":"m","status":"documentado_o_derivado_del_CAD","source":"GD05001, lámina 1; GD05000; cimentaciones 04/09"},{"label":"Cota inferior del apoyo","value":0.2,"unit":"m","status":"documentado_o_derivado_del_CAD","source":"GD05001, lámina 1; GD05000; cimentaciones 04/09"},{"label":"Cota superior del conjunto","value":5.55,"unit":"m","status":"documentado_o_derivado_del_CAD","source":"GD05001, lámina 1; GD05000; cimentaciones 04/09"},{"label":"Distancia entre ejes de columnas","value":1.75,"unit":"m","status":"documentado_o_derivado_del_CAD","source":"GD05001, lámina 1; GD05000; cimentaciones 04/09"}],"geometry":[{"label":"Extensión de malla X","value":0.16903271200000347,"unit":"m","status":"documentado_o_derivado_del_CAD","source":"GD05001, lámina 1; GD05000; cimentaciones 04/09"},{"label":"Extensión de malla Y","value":0.16903271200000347,"unit":"m","status":"documentado_o_derivado_del_CAD","source":"GD05001, lámina 1; GD05000; cimentaciones 04/09"},{"label":"Extensión de malla Z","value":5.3500000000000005,"unit":"m","status":"documentado_o_derivado_del_CAD","source":"GD05001, lámina 1; GD05000; cimentaciones 04/09"}],"notes":["Geometría de coordinación basada en planos recibidos; no sustituye el modelo de fabricación ni una medición certificada. Datum absoluto de proceso provisional."]} | {"axisStartManufacturerM":[24.925,26.075,0.2],"axisEndManufacturerM":[24.925,26.075,5.55],"assemblyReferenceENM":[24.925,24.325],"absoluteDatumConfirmed":false,"processZeroAbsoluteM":286.1,"basis":"Posición y cotas relativas contrastadas con C25–C28. Extremos de barras ajustados a caras para coordinación; uniones y soldaduras no representadas."} | ["found_0904_962f93347851e0"] | {"boundingBoxM":{"min":[60.66071,52.371295,1.3],"max":[60.829743,52.540327,6.65]},"extentsM":[0.169033,0.169033,5.35],"meshSurfaceM2":6.426912,"meshVolumeM3":0.01849,"closedSolid":true,"basis":"Geometría de coordinación basada en planos recibidos; no sustituye el modelo de fabricación ni una medición certificada. Datum absoluto de proceso provisional."} | {"elementId":"SL1201-COL-04","ifcGuid":"398KcwGM9LfxWgZy0QVQo$","ifcClass":"IfcMember","sourceDocumentId":"SOPC-PROCESS_020"} | SL1201-COL-04 | 0.15 | 0.006
SL1201 · travesaño INF 1 | {"documented":[{"label":"Sección exterior del tubo cuadrado","value":0.1,"unit":"m","status":"documentado_o_derivado_del_CAD","source":"GD05001, lámina 1; GD05000; cimentaciones 04/09"},{"label":"Espesor de pared","value":0.005,"unit":"m","status":"documentado_o_derivado_del_CAD","source":"GD05001, lámina 1; GD05000; cimentaciones 04/09"},{"label":"Cota inferior del apoyo","value":0.2,"unit":"m","status":"documentado_o_derivado_del_CAD","source":"GD05001, lámina 1; GD05000; cimentaciones 04/09"},{"label":"Cota superior del conjunto","value":5.55,"unit":"m","status":"documentado_o_derivado_del_CAD","source":"GD05001, lámina 1; GD05000; cimentaciones 04/09"},{"label":"Distancia entre ejes de columnas","value":1.75,"unit":"m","status":"documentado_o_derivado_del_CAD","source":"GD05001, lámina 1; GD05000; cimentaciones 04/09"}],"geometry":[{"label":"Extensión de malla X","value":1.5987097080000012,"unit":"m","status":"documentado_o_derivado_del_CAD","source":"GD05001, lámina 1; GD05000; cimentaciones 04/09"},{"label":"Extensión de malla Y","value":0.3169943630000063,"unit":"m","status":"documentado_o_derivado_del_CAD","source":"GD05001, lámina 1; GD05000; cimentaciones 04/09"},{"label":"Extensión de malla Z","value":0.10000000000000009,"unit":"m","status":"documentado_o_derivado_del_CAD","source":"GD05001, lámina 1; GD05000; cimentaciones 04/09"}],"notes":["Geometría de coordinación basada en planos recibidos; no sustituye el modelo de fabricación ni una medición certificada. Datum absoluto de proceso provisional."]} | {"axisStartManufacturerM":[25.0,24.325,2.075],"axisEndManufacturerM":[26.6,24.325,2.075],"assemblyReferenceENM":[24.925,24.325],"absoluteDatumConfirmed":false,"processZeroAbsoluteM":286.1,"basis":"Posición y cotas relativas contrastadas con C25–C28. Extremos de barras ajustados a caras para coordinación; uniones y soldaduras no representadas."} | ["found_0904_1b4f8e545510b9","found_0904_2eb1daa04dbdce"] | {"boundingBoxM":{"min":[60.57436,50.444444,3.125],"max":[62.17307,50.761438,3.225]},"extentsM":[1.59871,0.316994,0.1],"meshSurfaceM2":1.2838,"meshVolumeM3":0.00304,"closedSolid":true,"basis":"Geometría de coordinación basada en planos recibidos; no sustituye el modelo de fabricación ni una medición certificada. Datum absoluto de proceso provisional."} | {"elementId":"SL1201-INF-01","ifcGuid":"1xek9ibUjIyfjywexYaWol","ifcClass":"IfcMember","sourceDocumentId":"SOPC-PROCESS_020"} | SL1201-INF-01 | 0.1 | 0.005
SL1201 · travesaño INF 2 | {"documented":[{"label":"Sección exterior del tubo cuadrado","value":0.1,"unit":"m","status":"documentado_o_derivado_del_CAD","source":"GD05001, lámina 1; GD05000; cimentaciones 04/09"},{"label":"Espesor de pared","value":0.005,"unit":"m","status":"documentado_o_derivado_del_CAD","source":"GD05001, lámina 1; GD05000; cimentaciones 04/09"},{"label":"Cota inferior del apoyo","value":0.2,"unit":"m","status":"documentado_o_derivado_del_CAD","source":"GD05001, lámina 1; GD05000; cimentaciones 04/09"},{"label":"Cota superior del conjunto","value":5.55,"unit":"m","status":"documentado_o_derivado_del_CAD","source":"GD05001, lámina 1; GD05000; cimentaciones 04/09"},{"label":"Distancia entre ejes de columnas","value":1.75,"unit":"m","status":"documentado_o_derivado_del_CAD","source":"GD05001, lámina 1; GD05000; cimentaciones 04/09"}],"geometry":[{"label":"Extensión de malla X","value":0.31699436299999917,"unit":"m","status":"documentado_o_derivado_del_CAD","source":"GD05001, lámina 1; GD05000; cimentaciones 04/09"},{"label":"Extensión de malla Y","value":1.5987097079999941,"unit":"m","status":"documentado_o_derivado_del_CAD","source":"GD05001, lámina 1; GD05000; cimentaciones 04/09"},{"label":"Extensión de malla Z","value":0.10000000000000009,"unit":"m","status":"documentado_o_derivado_del_CAD","source":"GD05001, lámina 1; GD05000; cimentaciones 04/09"}],"notes":["Geometría de coordinación basada en planos recibidos; no sustituye el modelo de fabricación ni una medición certificada. Datum absoluto de proceso provisional."]} | {"axisStartManufacturerM":[26.675,24.4,2.075],"axisEndManufacturerM":[26.675,26.0,2.075],"assemblyReferenceENM":[24.925,24.325],"absoluteDatumConfirmed":false,"processZeroAbsoluteM":286.1,"basis":"Posición y cotas relativas contrastadas con C25–C28. Extremos de barras ajustados a caras para coordinación; uniones y soldaduras no representadas."} | ["found_0904_2eb1daa04dbdce","found_0904_b2ac6c4a33bf3e"] | {"boundingBoxM":{"min":[62.201242,50.551254,3.125],"max":[62.518236,52.149963,3.225]},"extentsM":[0.316994,1.59871,0.1],"meshSurfaceM2":1.2838,"meshVolumeM3":0.00304,"closedSolid":true,"basis":"Geometría de coordinación basada en planos recibidos; no sustituye el modelo de fabricación ni una medición certificada. Datum absoluto de proceso provisional."} | {"elementId":"SL1201-INF-02","ifcGuid":"0$2mHCRDjM5OJZPvSFWqq6","ifcClass":"IfcMember","sourceDocumentId":"SOPC-PROCESS_020"} | SL1201-INF-02 | 0.1 | 0.005
SL1201 · travesaño INF 3 | {"documented":[{"label":"Sección exterior del tubo cuadrado","value":0.1,"unit":"m","status":"documentado_o_derivado_del_CAD","source":"GD05001, lámina 1; GD05000; cimentaciones 04/09"},{"label":"Espesor de pared","value":0.005,"unit":"m","status":"documentado_o_derivado_del_CAD","source":"GD05001, lámina 1; GD05000; cimentaciones 04/09"},{"label":"Cota inferior del apoyo","value":0.2,"unit":"m","status":"documentado_o_derivado_del_CAD","source":"GD05001, lámina 1; GD05000; cimentaciones 04/09"},{"label":"Cota superior del conjunto","value":5.55,"unit":"m","status":"documentado_o_derivado_del_CAD","source":"GD05001, lámina 1; GD05000; cimentaciones 04/09"},{"label":"Distancia entre ejes de columnas","value":1.75,"unit":"m","status":"documentado_o_derivado_del_CAD","source":"GD05001, lámina 1; GD05000; cimentaciones 04/09"}],"geometry":[{"label":"Extensión de malla X","value":1.5987097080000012,"unit":"m","status":"documentado_o_derivado_del_CAD","source":"GD05001, lámina 1; GD05000; cimentaciones 04/09"},{"label":"Extensión de malla Y","value":0.31699436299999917,"unit":"m","status":"documentado_o_derivado_del_CAD","source":"GD05001, lámina 1; GD05000; cimentaciones 04/09"},{"label":"Extensión de malla Z","value":0.10000000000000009,"unit":"m","status":"documentado_o_derivado_del_CAD","source":"GD05001, lámina 1; GD05000; cimentaciones 04/09"}],"notes":["Geometría de coordinación basada en planos recibidos; no sustituye el modelo de fabricación ni una medición certificada. Datum absoluto de proceso provisional."]} | {"axisStartManufacturerM":[26.6,26.075,2.075],"axisEndManufacturerM":[25.0,26.075,2.075],"assemblyReferenceENM":[24.925,24.325],"absoluteDatumConfirmed":false,"processZeroAbsoluteM":286.1,"basis":"Posición y cotas relativas contrastadas con C25–C28. Extremos de barras ajustados a caras para coordinación; uniones y soldaduras no representadas."} | ["found_0904_b2ac6c4a33bf3e","found_0904_962f93347851e0"] | {"boundingBoxM":{"min":[60.812717,52.178136,3.125],"max":[62.411427,52.49513,3.225]},"extentsM":[1.59871,0.316994,0.1],"meshSurfaceM2":1.2838,"meshVolumeM3":0.00304,"closedSolid":true,"basis":"Geometría de coordinación basada en planos recibidos; no sustituye el modelo de fabricación ni una medición certificada. Datum absoluto de proceso provisional."} | {"elementId":"SL1201-INF-03","ifcGuid":"2_0vYNtVbTMwJPr3MaYdr3","ifcClass":"IfcMember","sourceDocumentId":"SOPC-PROCESS_020"} | SL1201-INF-03 | 0.1 | 0.005
SL1201 · travesaño INF 4 | {"documented":[{"label":"Sección exterior del tubo cuadrado","value":0.1,"unit":"m","status":"documentado_o_derivado_del_CAD","source":"GD05001, lámina 1; GD05000; cimentaciones 04/09"},{"label":"Espesor de pared","value":0.005,"unit":"m","status":"documentado_o_derivado_del_CAD","source":"GD05001, lámina 1; GD05000; cimentaciones 04/09"},{"label":"Cota inferior del apoyo","value":0.2,"unit":"m","status":"documentado_o_derivado_del_CAD","source":"GD05001, lámina 1; GD05000; cimentaciones 04/09"},{"label":"Cota superior del conjunto","value":5.55,"unit":"m","status":"documentado_o_derivado_del_CAD","source":"GD05001, lámina 1; GD05000; cimentaciones 04/09"},{"label":"Distancia entre ejes de columnas","value":1.75,"unit":"m","status":"documentado_o_derivado_del_CAD","source":"GD05001, lámina 1; GD05000; cimentaciones 04/09"}],"geometry":[{"label":"Extensión de malla X","value":0.31699436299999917,"unit":"m","status":"documentado_o_derivado_del_CAD","source":"GD05001, lámina 1; GD05000; cimentaciones 04/09"},{"label":"Extensión de malla Y","value":1.5987097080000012,"unit":"m","status":"documentado_o_derivado_del_CAD","source":"GD05001, lámina 1; GD05000; cimentaciones 04/09"},{"label":"Extensión de malla Z","value":0.10000000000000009,"unit":"m","status":"documentado_o_derivado_del_CAD","source":"GD05001, lámina 1; GD05000; cimentaciones 04/09"}],"notes":["Geometría de coordinación basada en planos recibidos; no sustituye el modelo de fabricación ni una medición certificada. Datum absoluto de proceso provisional."]} | {"axisStartManufacturerM":[24.925,26.0,2.075],"axisEndManufacturerM":[24.925,24.4,2.075],"assemblyReferenceENM":[24.925,24.325],"absoluteDatumConfirmed":false,"processZeroAbsoluteM":286.1,"basis":"Posición y cotas relativas contrastadas con C25–C28. Extremos de barras ajustados a caras para coordinación; uniones y soldaduras no representadas."} | ["found_0904_962f93347851e0","found_0904_1b4f8e545510b9"] | {"boundingBoxM":{"min":[60.467551,50.789611,3.125],"max":[60.784545,52.38832,3.225]},"extentsM":[0.316994,1.59871,0.1],"meshSurfaceM2":1.2838,"meshVolumeM3":0.00304,"closedSolid":true,"basis":"Geometría de coordinación basada en planos recibidos; no sustituye el modelo de fabricación ni una medición certificada. Datum absoluto de proceso provisional."} | {"elementId":"SL1201-INF-04","ifcGuid":"1TmHb57MjHC8XpaxkFVAzF","ifcClass":"IfcMember","sourceDocumentId":"SOPC-PROCESS_020"} | SL1201-INF-04 | 0.1 | 0.005
SL1201 · travesaño MED 1 | {"documented":[{"label":"Sección exterior del tubo cuadrado","value":0.1,"unit":"m","status":"documentado_o_derivado_del_CAD","source":"GD05001, lámina 1; GD05000; cimentaciones 04/09"},{"label":"Espesor de pared","value":0.005,"unit":"m","status":"documentado_o_derivado_del_CAD","source":"GD05001, lámina 1; GD05000; cimentaciones 04/09"},{"label":"Cota inferior del apoyo","value":0.2,"unit":"m","status":"documentado_o_derivado_del_CAD","source":"GD05001, lámina 1; GD05000; cimentaciones 04/09"},{"label":"Cota superior del conjunto","value":5.55,"unit":"m","status":"documentado_o_derivado_del_CAD","source":"GD05001, lámina 1; GD05000; cimentaciones 04/09"},{"label":"Distancia entre ejes de columnas","value":1.75,"unit":"m","status":"documentado_o_derivado_del_CAD","source":"GD05001, lámina 1; GD05000; cimentaciones 04/09"}],"geometry":[{"label":"Extensión de malla X","value":1.5987097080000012,"unit":"m","status":"documentado_o_derivado_del_CAD","source":"GD05001, lámina 1; GD05000; cimentaciones 04/09"},{"label":"Extensión de malla Y","value":0.3169943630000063,"unit":"m","status":"documentado_o_derivado_del_CAD","source":"GD05001, lámina 1; GD05000; cimentaciones 04/09"},{"label":"Extensión de malla Z","value":0.10000000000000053,"unit":"m","status":"documentado_o_derivado_del_CAD","source":"GD05001, lámina 1; GD05000; cimentaciones 04/09"}],"notes":["Geometría de coordinación basada en planos recibidos; no sustituye el modelo de fabricación ni una medición certificada. Datum absoluto de proceso provisional."]} | {"axisStartManufacturerM":[25.0,24.325,3.875],"axisEndManufacturerM":[26.6,24.325,3.875],"assemblyReferenceENM":[24.925,24.325],"absoluteDatumConfirmed":false,"processZeroAbsoluteM":286.1,"basis":"Posición y cotas relativas contrastadas con C25–C28. Extremos de barras ajustados a caras para coordinación; uniones y soldaduras no representadas."} | ["found_0904_1b4f8e545510b9","found_0904_2eb1daa04dbdce"] | {"boundingBoxM":{"min":[60.57436,50.444444,4.925],"max":[62.17307,50.761438,5.025]},"extentsM":[1.59871,0.316994,0.1],"meshSurfaceM2":1.2838,"meshVolumeM3":0.00304,"closedSolid":true,"basis":"Geometría de coordinación basada en planos recibidos; no sustituye el modelo de fabricación ni una medición certificada. Datum absoluto de proceso provisional."} | {"elementId":"SL1201-MED-01","ifcGuid":"1fwtQ_7ZvJtvEEaIQStntW","ifcClass":"IfcMember","sourceDocumentId":"SOPC-PROCESS_020"} | SL1201-MED-01 | 0.1 | 0.005
SL1201 · travesaño MED 2 | {"documented":[{"label":"Sección exterior del tubo cuadrado","value":0.1,"unit":"m","status":"documentado_o_derivado_del_CAD","source":"GD05001, lámina 1; GD05000; cimentaciones 04/09"},{"label":"Espesor de pared","value":0.005,"unit":"m","status":"documentado_o_derivado_del_CAD","source":"GD05001, lámina 1; GD05000; cimentaciones 04/09"},{"label":"Cota inferior del apoyo","value":0.2,"unit":"m","status":"documentado_o_derivado_del_CAD","source":"GD05001, lámina 1; GD05000; cimentaciones 04/09"},{"label":"Cota superior del conjunto","value":5.55,"unit":"m","status":"documentado_o_derivado_del_CAD","source":"GD05001, lámina 1; GD05000; cimentaciones 04/09"},{"label":"Distancia entre ejes de columnas","value":1.75,"unit":"m","status":"documentado_o_derivado_del_CAD","source":"GD05001, lámina 1; GD05000; cimentaciones 04/09"}],"geometry":[{"label":"Extensión de malla X","value":0.31699436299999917,"unit":"m","status":"documentado_o_derivado_del_CAD","source":"GD05001, lámina 1; GD05000; cimentaciones 04/09"},{"label":"Extensión de malla Y","value":1.5987097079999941,"unit":"m","status":"documentado_o_derivado_del_CAD","source":"GD05001, lámina 1; GD05000; cimentaciones 04/09"},{"label":"Extensión de malla Z","value":0.10000000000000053,"unit":"m","status":"documentado_o_derivado_del_CAD","source":"GD05001, lámina 1; GD05000; cimentaciones 04/09"}],"notes":["Geometría de coordinación basada en planos recibidos; no sustituye el modelo de fabricación ni una medición certificada. Datum absoluto de proceso provisional."]} | {"axisStartManufacturerM":[26.675,24.4,3.875],"axisEndManufacturerM":[26.675,26.0,3.875],"assemblyReferenceENM":[24.925,24.325],"absoluteDatumConfirmed":false,"processZeroAbsoluteM":286.1,"basis":"Posición y cotas relativas contrastadas con C25–C28. Extremos de barras ajustados a caras para coordinación; uniones y soldaduras no representadas."} | ["found_0904_2eb1daa04dbdce","found_0904_b2ac6c4a33bf3e"] | {"boundingBoxM":{"min":[62.201242,50.551254,4.925],"max":[62.518236,52.149963,5.025]},"extentsM":[0.316994,1.59871,0.1],"meshSurfaceM2":1.2838,"meshVolumeM3":0.00304,"closedSolid":true,"basis":"Geometría de coordinación basada en planos recibidos; no sustituye el modelo de fabricación ni una medición certificada. Datum absoluto de proceso provisional."} | {"elementId":"SL1201-MED-02","ifcGuid":"0JibaMq89GDPgtxSMDxfr6","ifcClass":"IfcMember","sourceDocumentId":"SOPC-PROCESS_020"} | SL1201-MED-02 | 0.1 | 0.005
SL1201 · travesaño MED 3 | {"documented":[{"label":"Sección exterior del tubo cuadrado","value":0.1,"unit":"m","status":"documentado_o_derivado_del_CAD","source":"GD05001, lámina 1; GD05000; cimentaciones 04/09"},{"label":"Espesor de pared","value":0.005,"unit":"m","status":"documentado_o_derivado_del_CAD","source":"GD05001, lámina 1; GD05000; cimentaciones 04/09"},{"label":"Cota inferior del apoyo","value":0.2,"unit":"m","status":"documentado_o_derivado_del_CAD","source":"GD05001, lámina 1; GD05000; cimentaciones 04/09"},{"label":"Cota superior del conjunto","value":5.55,"unit":"m","status":"documentado_o_derivado_del_CAD","source":"GD05001, lámina 1; GD05000; cimentaciones 04/09"},{"label":"Distancia entre ejes de columnas","value":1.75,"unit":"m","status":"documentado_o_derivado_del_CAD","source":"GD05001, lámina 1; GD05000; cimentaciones 04/09"}],"geometry":[{"label":"Extensión de malla X","value":1.5987097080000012,"unit":"m","status":"documentado_o_derivado_del_CAD","source":"GD05001, lámina 1; GD05000; cimentaciones 04/09"},{"label":"Extensión de malla Y","value":0.31699436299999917,"unit":"m","status":"documentado_o_derivado_del_CAD","source":"GD05001, lámina 1; GD05000; cimentaciones 04/09"},{"label":"Extensión de malla Z","value":0.10000000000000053,"unit":"m","status":"documentado_o_derivado_del_CAD","source":"GD05001, lámina 1; GD05000; cimentaciones 04/09"}],"notes":["Geometría de coordinación basada en planos recibidos; no sustituye el modelo de fabricación ni una medición certificada. Datum absoluto de proceso provisional."]} | {"axisStartManufacturerM":[26.6,26.075,3.875],"axisEndManufacturerM":[25.0,26.075,3.875],"assemblyReferenceENM":[24.925,24.325],"absoluteDatumConfirmed":false,"processZeroAbsoluteM":286.1,"basis":"Posición y cotas relativas contrastadas con C25–C28. Extremos de barras ajustados a caras para coordinación; uniones y soldaduras no representadas."} | ["found_0904_b2ac6c4a33bf3e","found_0904_962f93347851e0"] | {"boundingBoxM":{"min":[60.812717,52.178136,4.925],"max":[62.411427,52.49513,5.025]},"extentsM":[1.59871,0.316994,0.1],"meshSurfaceM2":1.2838,"meshVolumeM3":0.00304,"closedSolid":true,"basis":"Geometría de coordinación basada en planos recibidos; no sustituye el modelo de fabricación ni una medición certificada. Datum absoluto de proceso provisional."} | {"elementId":"SL1201-MED-03","ifcGuid":"3cdLPxi9THz9BH7O1LymkU","ifcClass":"IfcMember","sourceDocumentId":"SOPC-PROCESS_020"} | SL1201-MED-03 | 0.1 | 0.005
SL1201 · travesaño MED 4 | {"documented":[{"label":"Sección exterior del tubo cuadrado","value":0.1,"unit":"m","status":"documentado_o_derivado_del_CAD","source":"GD05001, lámina 1; GD05000; cimentaciones 04/09"},{"label":"Espesor de pared","value":0.005,"unit":"m","status":"documentado_o_derivado_del_CAD","source":"GD05001, lámina 1; GD05000; cimentaciones 04/09"},{"label":"Cota inferior del apoyo","value":0.2,"unit":"m","status":"documentado_o_derivado_del_CAD","source":"GD05001, lámina 1; GD05000; cimentaciones 04/09"},{"label":"Cota superior del conjunto","value":5.55,"unit":"m","status":"documentado_o_derivado_del_CAD","source":"GD05001, lámina 1; GD05000; cimentaciones 04/09"},{"label":"Distancia entre ejes de columnas","value":1.75,"unit":"m","status":"documentado_o_derivado_del_CAD","source":"GD05001, lámina 1; GD05000; cimentaciones 04/09"}],"geometry":[{"label":"Extensión de malla X","value":0.31699436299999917,"unit":"m","status":"documentado_o_derivado_del_CAD","source":"GD05001, lámina 1; GD05000; cimentaciones 04/09"},{"label":"Extensión de malla Y","value":1.5987097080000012,"unit":"m","status":"documentado_o_derivado_del_CAD","source":"GD05001, lámina 1; GD05000; cimentaciones 04/09"},{"label":"Extensión de malla Z","value":0.10000000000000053,"unit":"m","status":"documentado_o_derivado_del_CAD","source":"GD05001, lámina 1; GD05000; cimentaciones 04/09"}],"notes":["Geometría de coordinación basada en planos recibidos; no sustituye el modelo de fabricación ni una medición certificada. Datum absoluto de proceso provisional."]} | {"axisStartManufacturerM":[24.925,26.0,3.875],"axisEndManufacturerM":[24.925,24.4,3.875],"assemblyReferenceENM":[24.925,24.325],"absoluteDatumConfirmed":false,"processZeroAbsoluteM":286.1,"basis":"Posición y cotas relativas contrastadas con C25–C28. Extremos de barras ajustados a caras para coordinación; uniones y soldaduras no representadas."} | ["found_0904_962f93347851e0","found_0904_1b4f8e545510b9"] | {"boundingBoxM":{"min":[60.467551,50.789611,4.925],"max":[60.784545,52.38832,5.025]},"extentsM":[0.316994,1.59871,0.1],"meshSurfaceM2":1.2838,"meshVolumeM3":0.00304,"closedSolid":true,"basis":"Geometría de coordinación basada en planos recibidos; no sustituye el modelo de fabricación ni una medición certificada. Datum absoluto de proceso provisional."} | {"elementId":"SL1201-MED-04","ifcGuid":"0fh9d7PofU2uTJQYH4pq8q","ifcClass":"IfcMember","sourceDocumentId":"SOPC-PROCESS_020"} | SL1201-MED-04 | 0.1 | 0.005
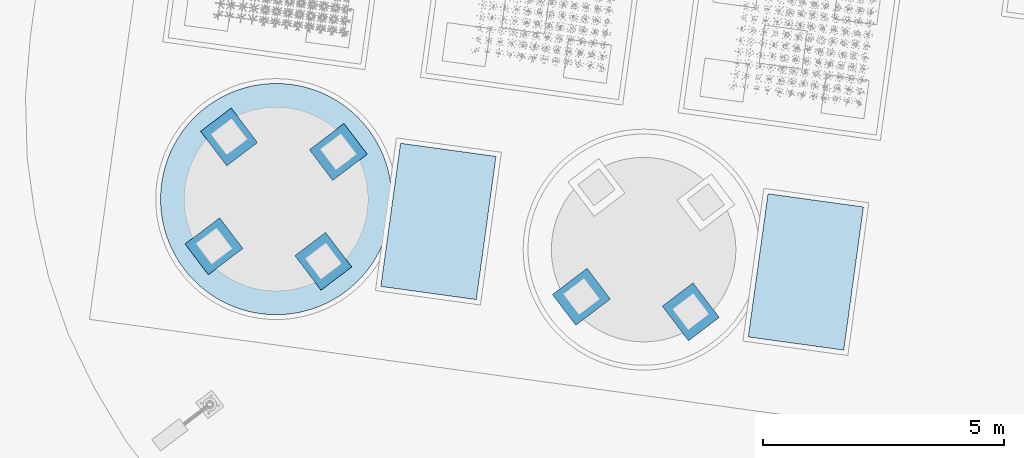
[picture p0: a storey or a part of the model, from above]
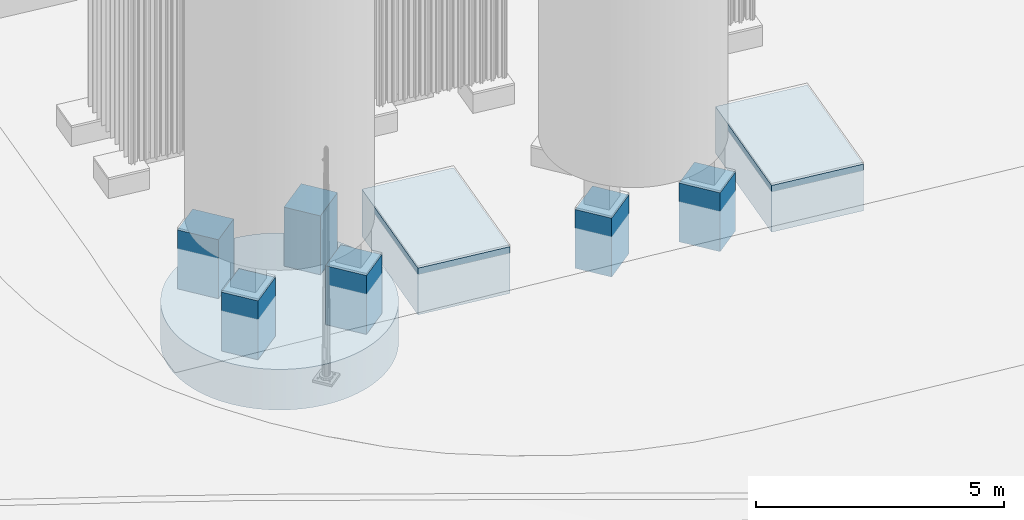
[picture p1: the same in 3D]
Properties of the parts of a building model (IFC4), part 96 of 134

# IfcMember (16)
Name | dimensions | positioning = PosicionYEstado | foundationIds | geometryMetrics | visualizationIdentity | Identificador | Sección exterior (m) = Sección exterior del tubo cuadrado (m) | Espesor (m) = Espesor de pared (m)
SL1201 · travesaño SUP 1 | {"documented":[{"label":"Sección exterior del tubo cuadrado","value":0.15,"unit":"m","status":"documentado_o_derivado_del_CAD","source":"GD05001, lámina 1; GD05000; cimentaciones 04/09"},{"label":"Espesor de pared","value":0.006,"unit":"m","status":"documentado_o_derivado_del_CAD","source":"GD05001, lámina 1; GD05000; cimentaciones 04/09"},{"label":"Cota inferior del apoyo","value":0.2,"unit":"m","status":"documentado_o_derivado_del_CAD","source":"GD05001, lámina 1; GD05000; cimentaciones 04/09"},{"label":"Cota superior del conjunto","value":5.55,"unit":"m","status":"documentado_o_derivado_del_CAD","source":"GD05001, lámina 1; GD05000; cimentaciones 04/09"},{"label":"Distancia entre ejes de columnas","value":1.75,"unit":"m","status":"documentado_o_derivado_del_CAD","source":"GD05001, lámina 1; GD05000; cimentaciones 04/09"}],"geometry":[{"label":"Extensión de malla X","value":1.6055199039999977,"unit":"m","status":"documentado_o_derivado_del_CAD","source":"GD05001, lámina 1; GD05000; cimentaciones 04/09"},{"label":"Extensión de malla Y","value":0.3665284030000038,"unit":"m","status":"documentado_o_derivado_del_CAD","source":"GD05001, lámina 1; GD05000; cimentaciones 04/09"},{"label":"Extensión de malla Z","value":0.15000000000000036,"unit":"m","status":"documentado_o_derivado_del_CAD","source":"GD05001, lámina 1; GD05000; cimentaciones 04/09"}],"notes":["Geometría de coordinación basada en planos recibidos; no sustituye el modelo de fabricación ni una medición certificada. Datum absoluto de proceso provisional."]} | {"axisStartManufacturerM":[25.0,24.325,5.475],"axisEndManufacturerM":[26.6,24.325,5.475],"assemblyReferenceENM":[24.925,24.325],"absoluteDatumConfirmed":false,"processZeroAbsoluteM":286.1,"basis":"Posición y cotas relativas contrastadas con C25–C28. Extremos de barras ajustados a caras para coordinación; uniones y soldaduras no representadas."} | ["found_0904_1b4f8e545510b9","found_0904_2eb1daa04dbdce"] | {"boundingBoxM":{"min":[60.570955,50.419677,6.5],"max":[62.176475,50.786205,6.65]},"extentsM":[1.60552,0.366528,0.15],"meshSurfaceM2":1.926912,"meshVolumeM3":0.00553,"closedSolid":true,"basis":"Geometría de coordinación basada en planos recibidos; no sustituye el modelo de fabricación ni una medición certificada. Datum absoluto de proceso provisional."} | {"elementId":"SL1201-SUP-01","ifcGuid":"0hD1go0PnK3u3VNyVE8Gtw","ifcClass":"IfcMember","sourceDocumentId":"SOPC-PROCESS_020"} | SL1201-SUP-01 | 0.15 | 0.006
SL1201 · travesaño SUP 2 | {"documented":[{"label":"Sección exterior del tubo cuadrado","value":0.15,"unit":"m","status":"documentado_o_derivado_del_CAD","source":"GD05001, lámina 1; GD05000; cimentaciones 04/09"},{"label":"Espesor de pared","value":0.006,"unit":"m","status":"documentado_o_derivado_del_CAD","source":"GD05001, lámina 1; GD05000; cimentaciones 04/09"},{"label":"Cota inferior del apoyo","value":0.2,"unit":"m","status":"documentado_o_derivado_del_CAD","source":"GD05001, lámina 1; GD05000; cimentaciones 04/09"},{"label":"Cota superior del conjunto","value":5.55,"unit":"m","status":"documentado_o_derivado_del_CAD","source":"GD05001, lámina 1; GD05000; cimentaciones 04/09"},{"label":"Distancia entre ejes de columnas","value":1.75,"unit":"m","status":"documentado_o_derivado_del_CAD","source":"GD05001, lámina 1; GD05000; cimentaciones 04/09"}],"geometry":[{"label":"Extensión de malla X","value":0.36652840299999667,"unit":"m","status":"documentado_o_derivado_del_CAD","source":"GD05001, lámina 1; GD05000; cimentaciones 04/09"},{"label":"Extensión de malla Y","value":1.6055199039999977,"unit":"m","status":"documentado_o_derivado_del_CAD","source":"GD05001, lámina 1; GD05000; cimentaciones 04/09"},{"label":"Extensión de malla Z","value":0.15000000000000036,"unit":"m","status":"documentado_o_derivado_del_CAD","source":"GD05001, lámina 1; GD05000; cimentaciones 04/09"}],"notes":["Geometría de coordinación basada en planos recibidos; no sustituye el modelo de fabricación ni una medición certificada. Datum absoluto de proceso provisional."]} | {"axisStartManufacturerM":[26.675,24.4,5.475],"axisEndManufacturerM":[26.675,26.0,5.475],"assemblyReferenceENM":[24.925,24.325],"absoluteDatumConfirmed":false,"processZeroAbsoluteM":286.1,"basis":"Posición y cotas relativas contrastadas con C25–C28. Extremos de barras ajustados a caras para coordinación; uniones y soldaduras no representadas."} | ["found_0904_2eb1daa04dbdce","found_0904_b2ac6c4a33bf3e"] | {"boundingBoxM":{"min":[62.176475,50.547849,6.5],"max":[62.543003,52.153368,6.65]},"extentsM":[0.366528,1.60552,0.15],"meshSurfaceM2":1.926912,"meshVolumeM3":0.00553,"closedSolid":true,"basis":"Geometría de coordinación basada en planos recibidos; no sustituye el modelo de fabricación ni una medición certificada. Datum absoluto de proceso provisional."} | {"elementId":"SL1201-SUP-02","ifcGuid":"3ehWmy1cLO2RQqHzlfRerb","ifcClass":"IfcMember","sourceDocumentId":"SOPC-PROCESS_020"} | SL1201-SUP-02 | 0.15 | 0.006
SL1201 · travesaño SUP 3 | {"documented":[{"label":"Sección exterior del tubo cuadrado","value":0.15,"unit":"m","status":"documentado_o_derivado_del_CAD","source":"GD05001, lámina 1; GD05000; cimentaciones 04/09"},{"label":"Espesor de pared","value":0.006,"unit":"m","status":"documentado_o_derivado_del_CAD","source":"GD05001, lámina 1; GD05000; cimentaciones 04/09"},{"label":"Cota inferior del apoyo","value":0.2,"unit":"m","status":"documentado_o_derivado_del_CAD","source":"GD05001, lámina 1; GD05000; cimentaciones 04/09"},{"label":"Cota superior del conjunto","value":5.55,"unit":"m","status":"documentado_o_derivado_del_CAD","source":"GD05001, lámina 1; GD05000; cimentaciones 04/09"},{"label":"Distancia entre ejes de columnas","value":1.75,"unit":"m","status":"documentado_o_derivado_del_CAD","source":"GD05001, lámina 1; GD05000; cimentaciones 04/09"}],"geometry":[{"label":"Extensión de malla X","value":1.6055199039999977,"unit":"m","status":"documentado_o_derivado_del_CAD","source":"GD05001, lámina 1; GD05000; cimentaciones 04/09"},{"label":"Extensión de malla Y","value":0.3665284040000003,"unit":"m","status":"documentado_o_derivado_del_CAD","source":"GD05001, lámina 1; GD05000; cimentaciones 04/09"},{"label":"Extensión de malla Z","value":0.15000000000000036,"unit":"m","status":"documentado_o_derivado_del_CAD","source":"GD05001, lámina 1; GD05000; cimentaciones 04/09"}],"notes":["Geometría de coordinación basada en planos recibidos; no sustituye el modelo de fabricación ni una medición certificada. Datum absoluto de proceso provisional."]} | {"axisStartManufacturerM":[26.6,26.075,5.475],"axisEndManufacturerM":[25.0,26.075,5.475],"assemblyReferenceENM":[24.925,24.325],"absoluteDatumConfirmed":false,"processZeroAbsoluteM":286.1,"basis":"Posición y cotas relativas contrastadas con C25–C28. Extremos de barras ajustados a caras para coordinación; uniones y soldaduras no representadas."} | ["found_0904_b2ac6c4a33bf3e","found_0904_962f93347851e0"] | {"boundingBoxM":{"min":[60.809312,52.153368,6.5],"max":[62.414832,52.519897,6.65]},"extentsM":[1.60552,0.366528,0.15],"meshSurfaceM2":1.926912,"meshVolumeM3":0.00553,"closedSolid":true,"basis":"Geometría de coordinación basada en planos recibidos; no sustituye el modelo de fabricación ni una medición certificada. Datum absoluto de proceso provisional."} | {"elementId":"SL1201-SUP-03","ifcGuid":"3A4PaOQE5Mt9BoVtiZ_94E","ifcClass":"IfcMember","sourceDocumentId":"SOPC-PROCESS_020"} | SL1201-SUP-03 | 0.15 | 0.006
SL1201 · travesaño SUP 4 | {"documented":[{"label":"Sección exterior del tubo cuadrado","value":0.15,"unit":"m","status":"documentado_o_derivado_del_CAD","source":"GD05001, lámina 1; GD05000; cimentaciones 04/09"},{"label":"Espesor de pared","value":0.006,"unit":"m","status":"documentado_o_derivado_del_CAD","source":"GD05001, lámina 1; GD05000; cimentaciones 04/09"},{"label":"Cota inferior del apoyo","value":0.2,"unit":"m","status":"documentado_o_derivado_del_CAD","source":"GD05001, lámina 1; GD05000; cimentaciones 04/09"},{"label":"Cota superior del conjunto","value":5.55,"unit":"m","status":"documentado_o_derivado_del_CAD","source":"GD05001, lámina 1; GD05000; cimentaciones 04/09"},{"label":"Distancia entre ejes de columnas","value":1.75,"unit":"m","status":"documentado_o_derivado_del_CAD","source":"GD05001, lámina 1; GD05000; cimentaciones 04/09"}],"geometry":[{"label":"Extensión de malla X","value":0.3665284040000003,"unit":"m","status":"documentado_o_derivado_del_CAD","source":"GD05001, lámina 1; GD05000; cimentaciones 04/09"},{"label":"Extensión de malla Y","value":1.6055199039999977,"unit":"m","status":"documentado_o_derivado_del_CAD","source":"GD05001, lámina 1; GD05000; cimentaciones 04/09"},{"label":"Extensión de malla Z","value":0.15000000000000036,"unit":"m","status":"documentado_o_derivado_del_CAD","source":"GD05001, lámina 1; GD05000; cimentaciones 04/09"}],"notes":["Geometría de coordinación basada en planos recibidos; no sustituye el modelo de fabricación ni una medición certificada. Datum absoluto de proceso provisional."]} | {"axisStartManufacturerM":[24.925,26.0,5.475],"axisEndManufacturerM":[24.925,24.4,5.475],"assemblyReferenceENM":[24.925,24.325],"absoluteDatumConfirmed":false,"processZeroAbsoluteM":286.1,"basis":"Posición y cotas relativas contrastadas con C25–C28. Extremos de barras ajustados a caras para coordinación; uniones y soldaduras no representadas."} | ["found_0904_962f93347851e0","found_0904_1b4f8e545510b9"] | {"boundingBoxM":{"min":[60.442784,50.786205,6.5],"max":[60.809312,52.391725,6.65]},"extentsM":[0.366528,1.60552,0.15],"meshSurfaceM2":1.926912,"meshVolumeM3":0.00553,"closedSolid":true,"basis":"Geometría de coordinación basada en planos recibidos; no sustituye el modelo de fabricación ni una medición certificada. Datum absoluto de proceso provisional."} | {"elementId":"SL1201-SUP-04","ifcGuid":"2MQ1165L9IKPoeaK40mb42","ifcClass":"IfcMember","sourceDocumentId":"SOPC-PROCESS_020"} | SL1201-SUP-04 | 0.15 | 0.006

# IfcMember: Tubo de perfil 35 × 2 mm (6)
In: Parcela industrial Jinhong
Description: Modelo de coordinación a partir de planos. Las dimensiones documentadas se separan de las simplificaciones gráficas y cotas de terreno interpoladas; no son cantidades certificadas de obra.; PredefinedType: USERDEFINED; Document: Detalles del vallado perimetral · paquete emitido 31/07/2026; Ubicación de muros perimetrales · CAD original; Implantación y rasantes de la parcela; Group: BIM · Vallado perimetral
JH_InformacionBIM - buildingId: site; buildingName: Urbanización y parcela; level: Exterior · vallado perimetral; category: Tubo de perfil 35 × 2 mm; ifcClass: IfcMember; status: derivado; source: {"documentId":"JH-U010-20260731","title":"Detalles del vallado perimetral · paquete emitido 31/07/2026","sheet":"U010 · página 11 del PDF original","date":"2026-07-10","issueDate":"2026-07-31","note":"Fecha del cajetín 10/07/2026; último paquete disponible de esta especialidad emitido 31/07/2026."}; planSource: {"documentId":"JH-U009-20260731","title":"Ubicación de muros perimetrales · CAD original","sheet":"U009 · página 10 del PDF original","date":"2026-07-10","issueDate":"2026-07-31"}; material: {"name":"Tubo de perfil 35 × 2 mm","status":"documentado","source":"U010 · detalle del vallado / acceso"}; appearance: {"profileId":"fence_metal","name":"Valla metálica · gris neutro","status":"criterio_visual","basis":"U010 indica valla de ensamblaje y tubo 35 × 2 mm. Color y protección superficial no confirmados; gris neutro de visualización."}; visualLayer: {"id":"fences","name":"Vallado perimetral","defaultVisible":true}; representationKind: geometria_derivada_de_planos; fenceBasis: Ejes y polígonos del CAD U009; alturas y materiales de U010. Las aberturas de acceso se mantienen libres.; terrainBasis: Apoyo coordinado con la superficie de urbanización ya representada; interpolación sobre sus triángulos, con proyección al borde próximo cuando el eje queda fuera. No constituye rasante de ejecución. Datum absoluto pendiente de confirmación.; positioning: {"Trazado":"Coordenadas originales del DWG, ETRS89 / UTM 29N, origen local 729400 / 4301550 m","Apoyo":"Apoyo coordinado con la superficie de urbanización ya representada; interpolación sobre sus triángulos, con proyección al borde próximo cuando el eje queda fuera. No constituye rasante de ejecución. Datum absoluto pendiente de confirmación."}; issues: ["U010 indica 286,10 m en el vértice noreste y U004 288,00 m. En el vértice noroeste U010 indica 286,65 y 285,65 m, frente a 285,70 m de U004. Se conservan las alturas relativas del detalle; las cotas absolutas requieren coordinación.","Las juntas, anclajes, armaduras, transición escalonada exacta y ejecución sobre pendientes no se consideran definidos por esta malla."]; quantityEligible: no
JH_Trazabilidad - Documento de origen: U009 / U010 · paquete 31/07/2026 · cajetín 10/07/2026; Capa BIM: Vallado perimetral; Aplicabilidad a mediciones: Geometría de coordinación; no usar como cantidades certificadas.; Categoria: Tubo de perfil 35 × 2 mm; ClaseIFC: IfcMember; EstadoDeInformacion: derivado; DocumentoFuente: {"documentId":"JH-U010-20260731","title":"Detalles del vallado perimetral · paquete emitido 31/07/2026","sheet":"U010 · página 11 del PDF original","date":"2026-07-10","issueDate":"2026-07-31","note":"Fecha del cajetín 10/07/2026; último paquete disponible de esta especialidad emitido 31/07/2026."}; IncidenciasPendientes: ["U010 indica 286,10 m en el vértice noreste y U004 288,00 m. En el vértice noroeste U010 indica 286,65 y 285,65 m, frente a 285,70 m de U004. Se conservan las alturas relativas del detalle; las cotas absolutas requieren coordinación.","Las juntas, anclajes, armaduras, transición escalonada exacta y ejecución sobre pendientes no se consideran definidos por esta malla."]; UsoDeLasMagnitudes: Modelo de coordinación a partir de planos. Las dimensiones documentadas se separan de las simplificaciones gráficas y cotas de terreno interpoladas; no son cantidades certificadas de obra.
JH_CriterioDePosicion - PosicionYEstado: {"Trazado":"Coordenadas originales del DWG, ETRS89 / UTM 29N, origen local 729400 / 4301550 m","Apoyo":"Apoyo coordinado con la superficie de urbanización ya representada; interpolación sobre sus triángulos, con proyección al borde próximo cuando el eje queda fuera. No constituye rasante de ejecución. Datum absoluto pendiente de confirmación."}
JH_EvidenciaDeMaterial - name: Tubo de perfil 35 × 2 mm; status: documentado; source: U010 · detalle del vallado / acceso
JH_DimensionesDocumentadas - Etiqueta del plano: Tubo de perfil de 35x2 mm de diámetro; Altura sobre basamento: 2 m; Módulo nominal: 2 m
JH_CapaBIM - IdentificadorCapa: fences; NombreCapa: Vallado perimetral; Funcion: Tubo de perfil 35 × 2 mm; VisibilidadInicial: yes
JH_Vallado - Criterio: Ejes y polígonos del CAD U009; alturas y materiales de U010. Las aberturas de acceso se mantienen libres.; PlanoDeImplantacion: {"documentId":"JH-U009-20260731","title":"Ubicación de muros perimetrales · CAD original","sheet":"U009 · página 10 del PDF original","date":"2026-07-10","issueDate":"2026-07-31"}; NivelDelTerreno: Apoyo coordinado con la superficie de urbanización ya representada; interpolación sobre sus triángulos, con proyección al borde próximo cuando el eje queda fuera. No constituye rasante de ejecución. Datum absoluto pendiente de confirmación.; Simplificaciones: [{"label":"Tubo representado","value":"Cilindro macizo simplificado de 35 mm; espesor hueco y empotramiento no desglosados","unit":""}]; IncluirEnMediciones: no
JH_AcabadoVisual - Perfil: fence_metal; Acabado: Valla metálica · gris neutro; ColorRGB: [0.43,0.48,0.49]; Rugosidad: 0.6; Metallicidad: 0.3; Estado: criterio_visual; Referencia: U010 indica valla de ensamblaje y tubo 35 × 2 mm. Color y protección superficial no confirmados; gris neutro de visualización.
Name | dimensions | classification | fenceSegmentId = Trazado CAD = Tramo | postCount | geometryMetrics | Identificador
Postes de vallado · Norte | {"documented":[{"label":"Etiqueta del plano","value":"Tubo de perfil de 35x2 mm de diámetro","unit":""},{"label":"Altura sobre basamento","value":2,"unit":"m"},{"label":"Módulo nominal","value":2,"unit":"m"}],"assumed":[{"label":"Tubo representado","value":"Cilindro macizo simplificado de 35 mm; espesor hueco y empotramiento no desglosados","unit":""}],"geometry":[{"label":"Extensión representada X","value":136.685324,"unit":"m"},{"label":"Extensión representada Y","value":18.871523,"unit":"m"},{"label":"Extensión representada Z","value":4.263874,"unit":"m"}]} | {"layerId":"fences","layerName":"Vallado perimetral","function":"Postes de vallado · Norte"} | FENCE-21B1A-1 | 70 | {"boundingBoxM":{"min":[0.5775,90.50212,1.194078],"max":[137.262824,109.373643,5.457952]},"extentsM":[136.685324,18.871523,4.263874],"meshSurfaceM2":15.267839,"meshVolumeM3":0.126006,"closedSolid":true,"basis":"Modelo de coordinación a partir de planos. Las dimensiones documentadas se separan de las simplificaciones gráficas y cotas de terreno interpoladas; no son cantidades certificadas de obra."} | FENCE-21B1A-1-POSTS
Postes de vallado · Este | {"documented":[{"label":"Etiqueta del plano","value":"Tubo de perfil de 35x2 mm de diámetro","unit":""},{"label":"Altura sobre basamento","value":2,"unit":"m"},{"label":"Módulo nominal","value":2,"unit":"m"}],"assumed":[{"label":"Tubo representado","value":"Cilindro macizo simplificado de 35 mm; espesor hueco y empotramiento no desglosados","unit":""}],"geometry":[{"label":"Extensión representada X","value":11.871805,"unit":"m"},{"label":"Extensión representada Y","value":85.906298,"unit":"m"},{"label":"Extensión representada Z","value":3.04874,"unit":"m"}]} | {"layerId":"fences","layerName":"Vallado perimetral","function":"Postes de vallado · Este"} | FENCE-21B1A-2 | 45 | {"boundingBoxM":{"min":[125.11792,2.647843,2.409212],"max":[136.989725,88.554141,5.457952]},"extentsM":[11.871805,85.906298,3.04874],"meshSurfaceM2":9.815036,"meshVolumeM3":0.081004,"closedSolid":true,"basis":"Modelo de coordinación a partir de planos. Las dimensiones documentadas se separan de las simplificaciones gráficas y cotas de terreno interpoladas; no son cantidades certificadas de obra."} | FENCE-21B1A-2-POSTS
Postes de vallado · Retorno sureste | {"documented":[{"label":"Etiqueta del plano","value":"Tubo de perfil de 35x2 mm de diámetro","unit":""},{"label":"Altura sobre basamento","value":2,"unit":"m"},{"label":"Módulo nominal","value":2,"unit":"m"}],"assumed":[{"label":"Tubo representado","value":"Cilindro macizo simplificado de 35 mm; espesor hueco y empotramiento no desglosados","unit":""}],"geometry":[{"label":"Extensión representada X","value":0.035,"unit":"m"},{"label":"Extensión representada Y","value":0.033287,"unit":"m"},{"label":"Extensión representada Z","value":2.0,"unit":"m"}]} | {"layerId":"fences","layerName":"Vallado perimetral","function":"Postes de vallado · Retorno sureste"} | FENCE-21B1A-3 | 1 | {"boundingBoxM":{"min":[123.136686,2.921351,2.369101],"max":[123.171686,2.954638,4.369101]},"extentsM":[0.035,0.033287,2.0],"meshSurfaceM2":0.218114,"meshVolumeM3":0.0018,"closedSolid":true,"basis":"Modelo de coordinación a partir de planos. Las dimensiones documentadas se separan de las simplificaciones gráficas y cotas de terreno interpoladas; no son cantidades certificadas de obra."} | FENCE-21B1A-3-POSTS
Postes de vallado · Sur | {"documented":[{"label":"Etiqueta del plano","value":"Tubo de perfil de 35x2 mm de diámetro","unit":""},{"label":"Altura sobre basamento","value":2,"unit":"m"},{"label":"Módulo nominal","value":2,"unit":"m"}],"assumed":[{"label":"Tubo representado","value":"Cilindro macizo simplificado de 35 mm; espesor hueco y empotramiento no desglosados","unit":""}],"geometry":[{"label":"Extensión representada X","value":115.582026,"unit":"m"},{"label":"Extensión representada Y","value":15.98442,"unit":"m"},{"label":"Extensión representada Z","value":3.120162,"unit":"m"}]} | {"layerId":"fences","layerName":"Vallado perimetral","function":"Postes de vallado · Sur"} | FENCE-21B33-1 | 60 | {"boundingBoxM":{"min":[6.004695,3.140184,1.248939],"max":[121.586721,19.124604,4.369101]},"extentsM":[115.582026,15.98442,3.120162],"meshSurfaceM2":13.086719,"meshVolumeM3":0.108006,"closedSolid":true,"basis":"Modelo de coordinación a partir de planos. Las dimensiones documentadas se separan de las simplificaciones gráficas y cotas de terreno interpoladas; no son cantidades certificadas de obra."} | FENCE-21B33-1-POSTS
Postes de vallado · Curva suroeste | {"documented":[{"label":"Etiqueta del plano","value":"Tubo de perfil de 35x2 mm de diámetro","unit":""},{"label":"Altura sobre basamento","value":2,"unit":"m"},{"label":"Módulo nominal","value":2,"unit":"m"}],"assumed":[{"label":"Tubo representado","value":"Cilindro macizo simplificado de 35 mm; espesor hueco y empotramiento no desglosados","unit":""}],"geometry":[{"label":"Extensión representada X","value":10.218981,"unit":"m"},{"label":"Extensión representada Y","value":17.346741,"unit":"m"},{"label":"Extensión representada Z","value":2.38,"unit":"m"}]} | {"layerId":"fences","layerName":"Vallado perimetral","function":"Postes de vallado · Curva suroeste"} | FENCE-21B33-2 | 12 | {"boundingBoxM":{"min":[-6.111148,19.603163,0.87],"max":[4.107833,36.949904,3.25]},"extentsM":[10.218981,17.346741,2.38],"meshSurfaceM2":2.617344,"meshVolumeM3":0.021601,"closedSolid":true,"basis":"Modelo de coordinación a partir de planos. Las dimensiones documentadas se separan de las simplificaciones gráficas y cotas de terreno interpoladas; no son cantidades certificadas de obra."} | FENCE-21B33-2-POSTS
Postes de vallado · Oeste | {"documented":[{"label":"Etiqueta del plano","value":"Tubo de perfil de 35x2 mm de diámetro","unit":""},{"label":"Altura sobre basamento","value":2,"unit":"m"},{"label":"Módulo nominal","value":2,"unit":"m"}],"assumed":[{"label":"Tubo representado","value":"Cilindro macizo simplificado de 35 mm; espesor hueco y empotramiento no desglosados","unit":""}],"geometry":[{"label":"Extensión representada X","value":4.842086,"unit":"m"},{"label":"Extensión representada Y","value":54.525794,"unit":"m"},{"label":"Extensión representada Z","value":2.373946,"unit":"m"}]} | {"layerId":"fences","layerName":"Vallado perimetral","function":"Postes de vallado · Oeste"} | FENCE-21B33-3 | 29 | {"boundingBoxM":{"min":[-5.625757,38.90888,0.870278],"max":[-0.783671,93.434674,3.244224]},"extentsM":[4.842086,54.525794,2.373946],"meshSurfaceM2":6.325246,"meshVolumeM3":0.052203,"closedSolid":true,"basis":"Modelo de coordinación a partir de planos. Las dimensiones documentadas se separan de las simplificaciones gráficas y cotas de terreno interpoladas; no son cantidades certificadas de obra."} | FENCE-21B33-3-POSTS

# IfcPipeSegment: Nitrógeno Ø 0,2 m · salida exterior
In: Parcela industrial Jinhong
Description: Cruce subterráneo provisional solicitado por el cliente. Salida al otro lado de la plataforma viaria; cotas, profundidad, soportes y conexión final pendientes del plano definitivo. No para construcción ni cantidades de obra.; PredefinedType: USERDEFINED; Document: Indicación del cliente y croquis sobre el visor · 08/09/2026; Corrección del cliente · cruce subterráneo completo del vial exterior; Planta general de tuberías de proceso; Isométricos de proceso; Plantas de tuberías de reserva; Group: BIM · Galería de nitrógeno · esquema
JH_CapaBIM - IdentificadorCapa: pipe_gallery; NombreCapa: Galería de nitrógeno · esquema; Funcion: Nitrógeno Ø 0,2 m · salida exterior; VisibilidadInicial: yes
JH_EsquemaProvisional - Estado: No para construcción; Origen: {"documentId":"JH-USER-CROSSING-20260909","title":"Corrección del cliente · cruce subterráneo completo del vial exterior","date":"2026-09-09","sheet":"Croquis rojo sobre el visor con entorno","note":"Entrar al subsuelo dentro de la parcela, atravesar calzada y aceras, y salir al otro lado. Geometría provisional de coordinación; diámetros aproximados 0,50 y 0,20 m."}; DimensionesSupuestas: [{"label":"Diámetro exterior aproximado","value":0.2,"unit":"m"},{"label":"Radio orientativo del codo","value":1,"unit":"m"},{"label":"Cruce de calzada y aceras en planta","value":23.403,"unit":"m"},{"label":"Retiro del eje tras la acera opuesta","value":3,"unit":"m"},{"label":"Cota del eje enterrado respecto al origen","value":-0.6741,"unit":"m"},{"label":"Altura de salida sobre el terreno orientativo","value":3,"unit":"m"}]; Posicion: {"Recorrido":"Bajante dentro de la parcela, cruce de toda la calzada y ambas aceras, subida en el margen opuesto.","Salida":"Eje situado aproximadamente 3 m después del borde exterior de la acera opuesta.","Cotas":"Superficie de contexto simplificada; profundidad de visualización, no cálculo de diseño.","Dimensiones":"Diámetros y radios provisionales; conservar hasta recibir plano."}; IncluirEnMediciones: no; Criterio: {"enabled":true,"basis":"Cruce subterráneo provisional solicitado por el cliente. Salida al otro lado de la plataforma viaria; cotas, profundidad, soportes y conexión final pendientes del plano definitivo. No para construcción ni cantidades de obra.","pending":["Plano definitivo de cruce","Profundidad y servicios enterrados","Protección y apoyos","Destino y conexión"]}
JH_TuberiaNitrogeno - Fluido: Nitrógeno; DiametroExteriorOrientativoM: 0.2; EjeRepresentadoM: [[51.084944,-13.766403,0.917728],[51.084944,-13.766403,2.917728],[51.084288,-13.771174,3.015746],[51.082327,-13.785439,3.112819],[51.079079,-13.809062,3.208013],[51.074576,-13.841814,3.300412],[51.068861,-13.883382,3.389125],[51.061989,-13.933363,3.473299],[51.054027,-13.991278,3.552122],[51.045051,-14.056567,3.624835],[51.035147,-14.128603,3.690739],[51.024411,-14.206691,3.749198],[51.012946,-14.290081,3.79965],[51.000863,-14.377967,3.841608],[50.988278,-14.469505,3.874669],[50.975312,-14.563812,3.898514],[50.96209,-14.659981,3.912913],[50.94874,-14.757084,3.917728],[50.744434,-16.243105,3.917728]]; Tramo: OUTLET; Enterrado: no; ClasePresionEspesorYUniones: Pendientes de ingeniería
JH_InformacionBIM - buildingId: site; buildingName: Urbanización y parcela; level: Exterior · esquema de servicios; category: Nitrógeno Ø 0,2 m · salida exterior; ifcClass: IfcPipeSegment; status: provisional; source: {"documentId":"JH-USER-CROSSING-20260909","title":"Corrección del cliente · cruce subterráneo completo del vial exterior","date":"2026-09-09","sheet":"Croquis rojo sobre el visor con entorno","note":"Entrar al subsuelo dentro de la parcela, atravesar calzada y aceras, y salir al otro lado. Geometría provisional de coordinación; diámetros aproximados 0,50 y 0,20 m."}; material: {"name":"Tubería de nitrógeno · azul de identificación","status":"provisional","source":"Material, espesor, aislamiento y protección pendientes de ingeniería."}; dimensions: {"documented":[],"assumed":[{"label":"Diámetro exterior aproximado","value":0.2,"unit":"m"},{"label":"Radio orientativo del codo","value":1,"unit":"m"},{"label":"Cruce de calzada y aceras en planta","value":23.403,"unit":"m"},{"label":"Retiro del eje tras la acera opuesta","value":3,"unit":"m"},{"label":"Cota del eje enterrado respecto al origen","value":-0.6741,"unit":"m"},{"label":"Altura de salida sobre el terreno orientativo","value":3,"unit":"m"}],"geometry":[{"label":"Extensión representada X","value":0.538795,"unit":"m"},{"label":"Extensión representada Y","value":2.58954,"unit":"m"},{"label":"Extensión representada Z","value":3.1,"unit":"m"}]}; appearance: {"profileId":"n2_pipe_small","name":"Tubería de nitrógeno · azul de identificación","status":"criterio_visual","basis":"Color y acabado orientativos para distinguir el esquema solicitado; material sin especificación confirmada."}; classification: {"layerId":"pipe_gallery","layerName":"Galería de nitrógeno · esquema","function":"Nitrógeno Ø 0,2 m · salida exterior"}; visualLayer: {"id":"pipe_gallery","name":"Galería de nitrógeno · esquema","defaultVisible":true}; representationKind: esquema_provisional_no_constructivo; conceptual: {"enabled":true,"basis":"Cruce subterráneo provisional solicitado por el cliente. Salida al otro lado de la plataforma viaria; cotas, profundidad, soportes y conexión final pendientes del plano definitivo. No para construcción ni cantidades de obra.","pending":["Plano definitivo de cruce","Profundidad y servicios enterrados","Protección y apoyos","Destino y conexión"]}; positioning: {"Recorrido":"Bajante dentro de la parcela, cruce de toda la calzada y ambas aceras, subida en el margen opuesto.","Salida":"Eje situado aproximadamente 3 m después del borde exterior de la acera opuesta.","Cotas":"Superficie de contexto simplificada; profundidad de visualización, no cálculo de diseño.","Dimensiones":"Diámetros y radios provisionales; conservar hasta recibir plano."}; quantityEligible: no; issues: ["Cruce subterráneo provisional solicitado por el cliente. Salida al otro lado de la plataforma viaria; cotas, profundidad, soportes y conexión final pendientes del plano definitivo. No para construcción ni cantidades de obra."]; medium: Nitrógeno; assemblyId: N2-200; pipeDiameterM: 0.2; pipeCenterlineModelM: [[51.084944,-13.766403,0.917728],[51.084944,-13.766403,2.917728],[51.084288,-13.771174,3.015746],[51.082327,-13.785439,3.112819],[51.079079,-13.809062,3.208013],[51.074576,-13.841814,3.300412],[51.068861,-13.883382,3.389125],[51.061989,-13.933363,3.473299],[51.054027,-13.991278,3.552122],[51.045051,-14.056567,3.624835],[51.035147,-14.128603,3.690739],[51.024411,-14.206691,3.749198],[51.012946,-14.290081,3.79965],[51.000863,-14.377967,3.841608],[50.988278,-14.469505,3.874669],[50.975312,-14.563812,3.898514],[50.96209,-14.659981,3.912913],[50.94874,-14.757084,3.917728],[50.744434,-16.243105,3.917728]]; isUnderground: no; pipePhase: OUTLET; connectionsStatus: Bocas representadas por cierre gráfico; no son tapas o uniones de fabricación.; geometryMetrics: {"boundingBoxM":{"min":[50.645366,-16.256726,0.917728],"max":[51.184161,-13.667186,4.017728]},"extentsM":[0.538795,2.58954,3.1],"meshSurfaceM2":3.238115,"meshVolumeM3":0.157412,"closedSolid":true,"basis":"Cruce subterráneo provisional solicitado por el cliente. Salida al otro lado de la plataforma viaria; cotas, profundidad, soportes y conexión final pendientes del plano definitivo. No para construcción ni cantidades de obra."}; RevisionDocumentalComplementaria: {"fecha": "2026-09-09", "estado": "Revisión documental; geometría conservada", "criterio": "Documentación complementaria recibida el 09/09/2026. Tuberías: paquete actualizado el 07/08; fechas y revisiones por plano. La recepción no cambia la fecha de diseño. Se mantienen cargas del 25/08 y cimentaciones recibidas el 04/09 frente a las versiones anteriores incluidas.", "documentos": ["SOPC-PROCESS_013", "SOPC-PROCESS_016", "SOPC-BACKUP_012"], "conclusiones": ["Se recibieron plantas, isométricos y tablas de líneas de proceso y reserva. Las plantas revisadas son proyecciones 2D; no contienen una red 3D importable. No se ha validado en estas fuentes el cruce exterior solicitado por el cliente ni sus diámetros aproximados de 0,50 y 0,20 m; se mantiene el trazado provisional actual."]}; IncidenciasPendientes: ["Cruce subterráneo provisional solicitado por el cliente. Salida al otro lado de la plataforma viaria; cotas, profundidad, soportes y conexión final pendientes del plano definitivo. No para construcción ni cantidades de obra.", "Se recibieron plantas, isométricos y tablas de líneas de proceso y reserva. Las plantas revisadas son proyecciones 2D; no contienen una red 3D importable. No se ha validado en estas fuentes el cruce exterior solicitado por el cliente ni sus diámetros aproximados de 0,50 y 0,20 m; se mantiene el trazado provisional actual."]
JH_Trazabilidad - Origen: Corrección del cliente · cruce subterráneo completo del vial exterior; Estado: Provisional · no para construcción; Capa BIM: Galería de nitrógeno · esquema; Mediciones de obra: Excluido; Identificador: N2-200-OUTLET; Categoria: Nitrógeno Ø 0,2 m · salida exterior; ClaseIFC: IfcPipeSegment; EstadoDeInformacion: provisional; DocumentoFuente: {"documentId":"JH-USER-CROSSING-20260909","title":"Corrección del cliente · cruce subterráneo completo del vial exterior","date":"2026-09-09","sheet":"Croquis rojo sobre el visor con entorno","note":"Entrar al subsuelo dentro de la parcela, atravesar calzada y aceras, y salir al otro lado. Geometría provisional de coordinación; diámetros aproximados 0,50 y 0,20 m."}; IncidenciasPendientes: ["Cruce subterráneo provisional solicitado por el cliente. Salida al otro lado de la plataforma viaria; cotas, profundidad, soportes y conexión final pendientes del plano definitivo. No para construcción ni cantidades de obra.", "Se recibieron plantas, isométricos y tablas de líneas de proceso y reserva. Las plantas revisadas son proyecciones 2D; no contienen una red 3D importable. No se ha validado en estas fuentes el cruce exterior solicitado por el cliente ni sus diámetros aproximados de 0,50 y 0,20 m; se mantiene el trazado provisional actual."]; UsoDeLasMagnitudes: Cruce subterráneo provisional solicitado por el cliente. Salida al otro lado de la plataforma viaria; cotas, profundidad, soportes y conexión final pendientes del plano definitivo. No para construcción ni cantidades de obra.; RevisionDocumentalComplementaria: {"fecha": "2026-09-09", "estado": "Revisión documental; geometría conservada", "criterio": "Documentación complementaria recibida el 09/09/2026. Tuberías: paquete actualizado el 07/08; fechas y revisiones por plano. La recepción no cambia la fecha de diseño. Se mantienen cargas del 25/08 y cimentaciones recibidas el 04/09 frente a las versiones anteriores incluidas.", "documentos": ["SOPC-PROCESS_013", "SOPC-PROCESS_016", "SOPC-BACKUP_012"], "conclusiones": ["Se recibieron plantas, isométricos y tablas de líneas de proceso y reserva. Las plantas revisadas son proyecciones 2D; no contienen una red 3D importable. No se ha validado en estas fuentes el cruce exterior solicitado por el cliente ni sus diámetros aproximados de 0,50 y 0,20 m; se mantiene el trazado provisional actual."]}
JH_CriterioDePosicion - PosicionYEstado: {"Recorrido":"Bajante dentro de la parcela, cruce de toda la calzada y ambas aceras, subida en el margen opuesto.","Salida":"Eje situado aproximadamente 3 m después del borde exterior de la acera opuesta.","Cotas":"Superficie de contexto simplificada; profundidad de visualización, no cálculo de diseño.","Dimensiones":"Diámetros y radios provisionales; conservar hasta recibir plano."}
JH_EvidenciaDeMaterial - name: Tubería de nitrógeno · azul de identificación; status: provisional; source: Material, espesor, aislamiento y protección pendientes de ingeniería.
JH_RevisionDocumental20260909 - Criterio: Documentación complementaria recibida el 09/09/2026. Tuberías: paquete actualizado el 07/08; fechas y revisiones por plano. La recepción no cambia la fecha de diseño. Se mantienen cargas del 25/08 y cimentaciones recibidas el 04/09 frente a las versiones anteriores incluidas.; Documentos: SOPC-PROCESS_013 | SOPC-PROCESS_016 | SOPC-BACKUP_012; Conclusiones: Se recibieron plantas, isométricos y tablas de líneas de proceso y reserva. Las plantas revisadas son proyecciones 2D; no contienen una red 3D importable. No se ha validado en estas fuentes el cruce exterior solicitado por el cliente ni sus diámetros aproximados de 0,50 y 0,20 m; se mantiene el trazado provisional actual.; GeometriaModificada: no

# IfcPipeSegment: Nitrógeno Ø 0,2 m · tramo aéreo y bajante
In: Parcela industrial Jinhong
Description: Cruce subterráneo provisional solicitado por el cliente. Salida al otro lado de la plataforma viaria; cotas, profundidad, soportes y conexión final pendientes del plano definitivo. No para construcción ni cantidades de obra.; PredefinedType: USERDEFINED; Document: Indicación del cliente y croquis sobre el visor · 08/09/2026; Corrección del cliente · cruce subterráneo completo del vial exterior; Planta general de tuberías de proceso; Isométricos de proceso; Plantas de tuberías de reserva; Group: BIM · Galería de nitrógeno · esquema
JH_CapaBIM - IdentificadorCapa: pipe_gallery; NombreCapa: Galería de nitrógeno · esquema; Funcion: Nitrógeno Ø 0,2 m · tramo aéreo y bajante; VisibilidadInicial: yes
JH_EsquemaProvisional - Estado: No para construcción; Origen: {"documentId":"JH-USER-N2-20260908","title":"Indicación del cliente y croquis sobre el visor · 08/09/2026","date":"2026-09-08","sheet":"Recorrido orientativo señalado en rojo","note":"Diámetros aproximados de 0,50 y 0,20 m solicitados por el cliente. No es un plano de ingeniería."}; DimensionesSupuestas: [{"label":"Diámetro exterior aproximado solicitado","value":0.2,"unit":"m"},{"label":"Separación transversal entre ejes","value":0.9,"unit":"m"},{"label":"Radio orientativo de codos","value":1.0,"unit":"m"},{"label":"Cota del eje aéreo respecto al origen del modelo","value":7.2,"unit":"m"},{"label":"Profundidad orientativa del eje enterrado","value":1.5,"unit":"m"},{"label":"Representación","value":"Envolvente maciza de visualización; espesor de pared y aislamiento no definidos","unit":""}]; Posicion: {"Trazado":"Desde el entorno de la caja fría hacia el borde sur indicado en el croquis; entrada al subsuelo dentro de la parcela.","Entrada al subsuelo":"Eje aproximado a 1,19 m del lindero; dos tuberías desplazadas ±0,45 m lateralmente.","Terreno exterior":"Nivel provisional prolongado desde la entrada al subsuelo; no se aporta levantamiento exterior ni se amplía la parcela."}; IncluirEnMediciones: no; Criterio: {"enabled":true,"basis":"Esquema provisional solicitado por el cliente. Trazado, altura, profundidad, soportes, material y conexiones pendientes de plano; no para construcción ni cómputo de cantidades.","pending":["Plano de ruta y servidumbre exterior","Alturas, profundidad y recubrimiento","Clase de tubería, presión, espesor, aislamiento y uniones","Cálculo de soportes, dilatación y conexiones reales"]}
JH_TuberiaNitrogeno - Fluido: Nitrógeno; DiametroExteriorOrientativoM: 0.2; EjeRepresentadoM: [[58.554194,40.561292,7.2],[54.978842,14.55592,7.2],[54.965492,14.458816,7.195185],[54.95227,14.362648,7.180785],[54.939304,14.268341,7.15694],[54.926719,14.176803,7.12388],[54.914636,14.088916,7.081921],[54.903171,14.005527,7.03147],[54.892435,13.927439,6.97301],[54.882531,13.855403,6.907107],[54.873555,13.790113,6.834393],[54.865592,13.732199,6.75557],[54.858721,13.682218,6.671397],[54.853006,13.64065,6.582683],[54.848503,13.607898,6.490285],[54.845255,13.584275,6.39509],[54.843294,13.57001,6.298017],[54.842638,13.565239,6.2],[54.842638,13.565239,1.261512]]; Tramo: AERIAL; Enterrado: no; ClasePresionEspesorYUniones: Pendientes de ingeniería
JH_InformacionBIM - buildingId: site; buildingName: Urbanización y parcela; level: Exterior · esquema de servicios; category: Nitrógeno Ø 0,2 m · tramo aéreo y bajante; ifcClass: IfcPipeSegment; status: provisional; source: {"documentId":"JH-USER-CROSSING-20260909","title":"Corrección del cliente · cruce subterráneo completo del vial exterior","date":"2026-09-09","sheet":"Croquis rojo sobre el visor con entorno","note":"Entrar al subsuelo dentro de la parcela, atravesar calzada y aceras, y salir al otro lado. Geometría provisional de coordinación; diámetros aproximados 0,50 y 0,20 m."}; material: {"name":"Tubería de nitrógeno · azul de identificación","status":"provisional","source":"Material, espesor, aislamiento y protección pendientes de ingeniería."}; dimensions: {"documented":[],"assumed":[{"label":"Diámetro exterior aproximado solicitado","value":0.2,"unit":"m"},{"label":"Separación transversal entre ejes","value":0.9,"unit":"m"},{"label":"Radio orientativo de codos","value":1.0,"unit":"m"},{"label":"Cota del eje aéreo respecto al origen del modelo","value":7.2,"unit":"m"},{"label":"Profundidad del eje enterrado bajo la entrada adoptada","value":1.935608,"unit":"m"},{"label":"Representación","value":"Envolvente maciza de visualización; espesor de pared y aislamiento no definidos","unit":""}],"geometry":[{"label":"Extensión representada X","value":3.909842,"unit":"m"},{"label":"Extensión representada Y","value":27.10889,"unit":"m"},{"label":"Extensión representada Z","value":6.038488,"unit":"m"}]}; appearance: {"profileId":"n2_pipe_small","name":"Tubería de nitrógeno · azul de identificación","status":"criterio_visual","basis":"Color y acabado orientativos para distinguir el esquema solicitado; material sin especificación confirmada."}; classification: {"layerId":"pipe_gallery","layerName":"Galería de nitrógeno · esquema","function":"Nitrógeno Ø 0,2 m · tramo aéreo y bajante"}; visualLayer: {"id":"pipe_gallery","name":"Galería de nitrógeno · esquema","defaultVisible":true}; representationKind: esquema_provisional_no_constructivo; conceptual: {"enabled":true,"basis":"Esquema provisional solicitado por el cliente. Trazado, altura, profundidad, soportes, material y conexiones pendientes de plano; no para construcción ni cómputo de cantidades.","pending":["Plano de ruta y servidumbre exterior","Alturas, profundidad y recubrimiento","Clase de tubería, presión, espesor, aislamiento y uniones","Cálculo de soportes, dilatación y conexiones reales"]}; positioning: {"Trazado":"Desde el entorno de la caja fría hacia el borde sur indicado en el croquis; entrada al subsuelo dentro de la parcela.","Entrada al subsuelo":"Eje aproximado a 1,19 m del lindero; dos tuberías desplazadas ±0,45 m lateralmente.","Terreno exterior":"Nivel provisional prolongado desde la entrada al subsuelo; no se aporta levantamiento exterior ni se amplía la parcela."}; quantityEligible: no; issues: ["Esquema provisional solicitado por el cliente. Trazado, altura, profundidad, soportes, material y conexiones pendientes de plano; no para construcción ni cómputo de cantidades.","La posición de la salida exterior y el terreno de contexto son orientativos, sin confirmar propiedad, permisos ni destino de conexión."]; medium: Nitrógeno; assemblyId: N2-200; pipeDiameterM: 0.2; pipeCenterlineModelM: [[58.554194,40.561292,7.2],[54.978842,14.55592,7.2],[54.965492,14.458816,7.195185],[54.95227,14.362648,7.180785],[54.939304,14.268341,7.15694],[54.926719,14.176803,7.12388],[54.914636,14.088916,7.081921],[54.903171,14.005527,7.03147],[54.892435,13.927439,6.97301],[54.882531,13.855403,6.907107],[54.873555,13.790113,6.834393],[54.865592,13.732199,6.75557],[54.858721,13.682218,6.671397],[54.853006,13.64065,6.582683],[54.848503,13.607898,6.490285],[54.845255,13.584275,6.39509],[54.843294,13.57001,6.298017],[54.842638,13.565239,6.2],[54.842638,13.565239,1.261512]]; isUnderground: no; pipePhase: AERIAL; connectionsStatus: Bocas representadas por cierre gráfico; no son tapas o uniones de fabricación.; geometryMetrics: {"boundingBoxM":{"min":[54.74342,13.466022,1.261512],"max":[58.653262,40.574912,7.3]},"extentsM":[3.909842,27.10889,6.038488],"meshSurfaceM2":20.585692,"meshVolumeM3":1.017372,"closedSolid":true,"basis":"Esquema provisional de coordinación autorizado por el cliente. Tuberías, soportes, alumbrado e hidrantes con dimensiones y posiciones orientativas; no para construcción ni cómputo de cantidades."}; crossingReference: {"documentId":"JH-USER-CROSSING-20260909","title":"Corrección del cliente · cruce subterráneo completo del vial exterior","date":"2026-09-09","sheet":"Croquis rojo sobre el visor con entorno","note":"Entrar al subsuelo dentro de la parcela, atravesar calzada y aceras, y salir al otro lado. Geometría provisional de coordinación; diámetros aproximados 0,50 y 0,20 m."}; RevisionDocumentalComplementaria: {"fecha": "2026-09-09", "estado": "Revisión documental; geometría conservada", "criterio": "Documentación complementaria recibida el 09/09/2026. Tuberías: paquete actualizado el 07/08; fechas y revisiones por plano. La recepción no cambia la fecha de diseño. Se mantienen cargas del 25/08 y cimentaciones recibidas el 04/09 frente a las versiones anteriores incluidas.", "documentos": ["SOPC-PROCESS_013", "SOPC-PROCESS_016", "SOPC-BACKUP_012"], "conclusiones": ["Se recibieron plantas, isométricos y tablas de líneas de proceso y reserva. Las plantas revisadas son proyecciones 2D; no contienen una red 3D importable. No se ha validado en estas fuentes el cruce exterior solicitado por el cliente ni sus diámetros aproximados de 0,50 y 0,20 m; se mantiene el trazado provisional actual."]}; IncidenciasPendientes: ["Esquema provisional solicitado por el cliente. Trazado, altura, profundidad, soportes, material y conexiones pendientes de plano; no para construcción ni cómputo de cantidades.", "La posición de la salida exterior y el terreno de contexto son orientativos, sin confirmar propiedad, permisos ni destino de conexión.", "Se recibieron plantas, isométricos y tablas de líneas de proceso y reserva. Las plantas revisadas son proyecciones 2D; no contienen una red 3D importable. No se ha validado en estas fuentes el cruce exterior solicitado por el cliente ni sus diámetros aproximados de 0,50 y 0,20 m; se mantiene el trazado provisional actual."]
JH_Trazabilidad - Origen: Corrección del cliente · cruce subterráneo completo del vial exterior; Estado: Provisional · no para construcción; Capa BIM: Galería de nitrógeno · esquema; Mediciones de obra: Excluido; Identificador: N2-200-AERIAL; Categoria: Nitrógeno Ø 0,2 m · tramo aéreo y bajante; ClaseIFC: IfcPipeSegment; EstadoDeInformacion: provisional; DocumentoFuente: {"documentId":"JH-USER-CROSSING-20260909","title":"Corrección del cliente · cruce subterráneo completo del vial exterior","date":"2026-09-09","sheet":"Croquis rojo sobre el visor con entorno","note":"Entrar al subsuelo dentro de la parcela, atravesar calzada y aceras, y salir al otro lado. Geometría provisional de coordinación; diámetros aproximados 0,50 y 0,20 m."}; IncidenciasPendientes: ["Esquema provisional solicitado por el cliente. Trazado, altura, profundidad, soportes, material y conexiones pendientes de plano; no para construcción ni cómputo de cantidades.", "La posición de la salida exterior y el terreno de contexto son orientativos, sin confirmar propiedad, permisos ni destino de conexión.", "Se recibieron plantas, isométricos y tablas de líneas de proceso y reserva. Las plantas revisadas son proyecciones 2D; no contienen una red 3D importable. No se ha validado en estas fuentes el cruce exterior solicitado por el cliente ni sus diámetros aproximados de 0,50 y 0,20 m; se mantiene el trazado provisional actual."]; UsoDeLasMagnitudes: Cruce subterráneo provisional solicitado por el cliente. Salida al otro lado de la plataforma viaria; cotas, profundidad, soportes y conexión final pendientes del plano definitivo. No para construcción ni cantidades de obra.; RevisionDocumentalComplementaria: {"fecha": "2026-09-09", "estado": "Revisión documental; geometría conservada", "criterio": "Documentación complementaria recibida el 09/09/2026. Tuberías: paquete actualizado el 07/08; fechas y revisiones por plano. La recepción no cambia la fecha de diseño. Se mantienen cargas del 25/08 y cimentaciones recibidas el 04/09 frente a las versiones anteriores incluidas.", "documentos": ["SOPC-PROCESS_013", "SOPC-PROCESS_016", "SOPC-BACKUP_012"], "conclusiones": ["Se recibieron plantas, isométricos y tablas de líneas de proceso y reserva. Las plantas revisadas son proyecciones 2D; no contienen una red 3D importable. No se ha validado en estas fuentes el cruce exterior solicitado por el cliente ni sus diámetros aproximados de 0,50 y 0,20 m; se mantiene el trazado provisional actual."]}
JH_CriterioDePosicion - PosicionYEstado: {"Trazado":"Desde el entorno de la caja fría hacia el borde sur indicado en el croquis; entrada al subsuelo dentro de la parcela.","Entrada al subsuelo":"Eje aproximado a 1,19 m del lindero; dos tuberías desplazadas ±0,45 m lateralmente.","Terreno exterior":"Nivel provisional prolongado desde la entrada al subsuelo; no se aporta levantamiento exterior ni se amplía la parcela."}
JH_EvidenciaDeMaterial - name: Tubería de nitrógeno · azul de identificación; status: provisional; source: Material, espesor, aislamiento y protección pendientes de ingeniería.
JH_RevisionDocumental20260909 - Criterio: Documentación complementaria recibida el 09/09/2026. Tuberías: paquete actualizado el 07/08; fechas y revisiones por plano. La recepción no cambia la fecha de diseño. Se mantienen cargas del 25/08 y cimentaciones recibidas el 04/09 frente a las versiones anteriores incluidas.; Documentos: SOPC-PROCESS_013 | SOPC-PROCESS_016 | SOPC-BACKUP_012; Conclusiones: Se recibieron plantas, isométricos y tablas de líneas de proceso y reserva. Las plantas revisadas son proyecciones 2D; no contienen una red 3D importable. No se ha validado en estas fuentes el cruce exterior solicitado por el cliente ni sus diámetros aproximados de 0,50 y 0,20 m; se mantiene el trazado provisional actual.; GeometriaModificada: no

# IfcPipeSegment: Nitrógeno Ø 0,2 m · tramo enterrado
In: Parcela industrial Jinhong
Description: Cruce subterráneo provisional solicitado por el cliente. Salida al otro lado de la plataforma viaria; cotas, profundidad, soportes y conexión final pendientes del plano definitivo. No para construcción ni cantidades de obra.; PredefinedType: USERDEFINED; Document: Indicación del cliente y croquis sobre el visor · 08/09/2026; Corrección del cliente · cruce subterráneo completo del vial exterior; Planta general de tuberías de proceso; Isométricos de proceso; Plantas de tuberías de reserva; Group: BIM · Nitrógeno · tramo enterrado
JH_CapaBIM - IdentificadorCapa: pipe_underground; NombreCapa: Nitrógeno · tramo enterrado; Funcion: Nitrógeno Ø 0,2 m · tramo enterrado; VisibilidadInicial: yes
JH_EsquemaProvisional - Estado: No para construcción; Origen: {"documentId":"JH-USER-CROSSING-20260909","title":"Corrección del cliente · cruce subterráneo completo del vial exterior","date":"2026-09-09","sheet":"Croquis rojo sobre el visor con entorno","note":"Entrar al subsuelo dentro de la parcela, atravesar calzada y aceras, y salir al otro lado. Geometría provisional de coordinación; diámetros aproximados 0,50 y 0,20 m."}; DimensionesSupuestas: [{"label":"Diámetro exterior aproximado","value":0.2,"unit":"m"},{"label":"Radio orientativo del codo","value":1,"unit":"m"},{"label":"Cruce de calzada y aceras en planta","value":23.403,"unit":"m"},{"label":"Retiro del eje tras la acera opuesta","value":3,"unit":"m"},{"label":"Cota del eje enterrado respecto al origen","value":-0.6741,"unit":"m"},{"label":"Altura de salida sobre el terreno orientativo","value":3,"unit":"m"}]; Posicion: {"Recorrido":"Bajante dentro de la parcela, cruce de toda la calzada y ambas aceras, subida en el margen opuesto.","Salida":"Eje situado aproximadamente 3 m después del borde exterior de la acera opuesta.","Cotas":"Superficie de contexto simplificada; profundidad de visualización, no cálculo de diseño.","Dimensiones":"Diámetros y radios provisionales; conservar hasta recibir plano."}; IncluirEnMediciones: no; Criterio: {"enabled":true,"basis":"Cruce subterráneo provisional solicitado por el cliente. Salida al otro lado de la plataforma viaria; cotas, profundidad, soportes y conexión final pendientes del plano definitivo. No para construcción ni cantidades de obra.","pending":["Plano definitivo de cruce","Profundidad y servicios enterrados","Protección y apoyos","Destino y conexión"]}
JH_TuberiaNitrogeno - Fluido: Nitrógeno; DiametroExteriorOrientativoM: 0.2; EjeRepresentadoM: [[54.842638,13.565239,1.261512],[54.842638,13.565239,0.325904],[54.841982,13.560469,0.227887],[54.840021,13.546204,0.130814],[54.836773,13.522581,0.03562],[54.83227,13.489828,-0.056779],[54.826555,13.448261,-0.145492],[54.819683,13.398279,-0.229666],[54.811721,13.340365,-0.308489],[54.802745,13.275075,-0.381202],[54.792841,13.20304,-0.447106],[54.782105,13.124951,-0.505565],[54.77064,13.041562,-0.556017],[54.758557,12.953675,-0.597975],[54.745972,12.862138,-0.631036],[54.733006,12.767831,-0.654881],[54.719784,12.671662,-0.66928],[54.706434,12.574558,-0.674096],[51.221148,-12.775723,-0.674096],[51.207797,-12.872826,-0.66928],[51.194576,-12.968995,-0.654881],[51.18161,-13.063302,-0.631036],[51.169025,-13.15484,-0.597975],[51.156942,-13.242726,-0.556017],[51.145477,-13.326115,-0.505565],[51.134741,-13.404204,-0.447106],[51.124837,-13.47624,-0.381202],[51.115861,-13.541529,-0.308489],[51.107898,-13.599444,-0.229666],[51.101026,-13.649425,-0.145492],[51.095312,-13.690992,-0.056779],[51.090809,-13.723745,0.03562],[51.087561,-13.747368,0.130814],[51.0856,-13.761633,0.227887],[51.084944,-13.766403,0.325904],[51.084944,-13.766403,0.917728]]; Tramo: BURIED; Enterrado: yes; ClasePresionEspesorYUniones: Pendientes de ingeniería
JH_InformacionBIM - buildingId: site; buildingName: Urbanización y parcela; level: Exterior · esquema de servicios; category: Nitrógeno Ø 0,2 m · tramo enterrado; ifcClass: IfcPipeSegment; status: provisional; source: {"documentId":"JH-USER-CROSSING-20260909","title":"Corrección del cliente · cruce subterráneo completo del vial exterior","date":"2026-09-09","sheet":"Croquis rojo sobre el visor con entorno","note":"Entrar al subsuelo dentro de la parcela, atravesar calzada y aceras, y salir al otro lado. Geometría provisional de coordinación; diámetros aproximados 0,50 y 0,20 m."}; material: {"name":"Tubería de nitrógeno · azul de identificación","status":"provisional","source":"Material, espesor, aislamiento y protección pendientes de ingeniería."}; dimensions: {"documented":[],"assumed":[{"label":"Diámetro exterior aproximado","value":0.2,"unit":"m"},{"label":"Radio orientativo del codo","value":1,"unit":"m"},{"label":"Cruce de calzada y aceras en planta","value":23.403,"unit":"m"},{"label":"Retiro del eje tras la acera opuesta","value":3,"unit":"m"},{"label":"Cota del eje enterrado respecto al origen","value":-0.6741,"unit":"m"},{"label":"Altura de salida sobre el terreno orientativo","value":3,"unit":"m"}],"geometry":[{"label":"Extensión representada X","value":3.95613,"unit":"m"},{"label":"Extensión representada Y","value":27.530078,"unit":"m"},{"label":"Extensión representada Z","value":2.035608,"unit":"m"}]}; appearance: {"profileId":"n2_pipe_small","name":"Tubería de nitrógeno · azul de identificación","status":"criterio_visual","basis":"Color y acabado orientativos para distinguir el esquema solicitado; material sin especificación confirmada."}; classification: {"layerId":"pipe_underground","layerName":"Nitrógeno · tramo enterrado","function":"Nitrógeno Ø 0,2 m · tramo enterrado"}; visualLayer: {"id":"pipe_underground","name":"Nitrógeno · tramo enterrado","defaultVisible":true}; representationKind: esquema_provisional_no_constructivo; conceptual: {"enabled":true,"basis":"Cruce subterráneo provisional solicitado por el cliente. Salida al otro lado de la plataforma viaria; cotas, profundidad, soportes y conexión final pendientes del plano definitivo. No para construcción ni cantidades de obra.","pending":["Plano definitivo de cruce","Profundidad y servicios enterrados","Protección y apoyos","Destino y conexión"]}; positioning: {"Recorrido":"Bajante dentro de la parcela, cruce de toda la calzada y ambas aceras, subida en el margen opuesto.","Salida":"Eje situado aproximadamente 3 m después del borde exterior de la acera opuesta.","Cotas":"Superficie de contexto simplificada; profundidad de visualización, no cálculo de diseño.","Dimensiones":"Diámetros y radios provisionales; conservar hasta recibir plano."}; quantityEligible: no; issues: ["Cruce subterráneo provisional solicitado por el cliente. Salida al otro lado de la plataforma viaria; cotas, profundidad, soportes y conexión final pendientes del plano definitivo. No para construcción ni cantidades de obra."]; medium: Nitrógeno; assemblyId: N2-200; pipeDiameterM: 0.2; pipeCenterlineModelM: [[54.842638,13.565239,1.261512],[54.842638,13.565239,0.325904],[54.841982,13.560469,0.227887],[54.840021,13.546204,0.130814],[54.836773,13.522581,0.03562],[54.83227,13.489828,-0.056779],[54.826555,13.448261,-0.145492],[54.819683,13.398279,-0.229666],[54.811721,13.340365,-0.308489],[54.802745,13.275075,-0.381202],[54.792841,13.20304,-0.447106],[54.782105,13.124951,-0.505565],[54.77064,13.041562,-0.556017],[54.758557,12.953675,-0.597975],[54.745972,12.862138,-0.631036],[54.733006,12.767831,-0.654881],[54.719784,12.671662,-0.66928],[54.706434,12.574558,-0.674096],[51.221148,-12.775723,-0.674096],[51.207797,-12.872826,-0.66928],[51.194576,-12.968995,-0.654881],[51.18161,-13.063302,-0.631036],[51.169025,-13.15484,-0.597975],[51.156942,-13.242726,-0.556017],[51.145477,-13.326115,-0.505565],[51.134741,-13.404204,-0.447106],[51.124837,-13.47624,-0.381202],[51.115861,-13.541529,-0.308489],[51.107898,-13.599444,-0.229666],[51.101026,-13.649425,-0.145492],[51.095312,-13.690992,-0.056779],[51.090809,-13.723745,0.03562],[51.087561,-13.747368,0.130814],[51.0856,-13.761633,0.227887],[51.084944,-13.766403,0.325904],[51.084944,-13.766403,0.917728]]; isUnderground: yes; pipePhase: BURIED; connectionsStatus: Bocas representadas por cierre gráfico; no son tapas o uniones de fabricación.; geometryMetrics: {"boundingBoxM":{"min":[50.985726,-13.865621,-0.774096],"max":[54.941856,13.664457,1.261512]},"extentsM":[3.95613,27.530078,2.035608],"meshSurfaceM2":19.017409,"meshVolumeM3":0.939597,"closedSolid":true,"basis":"Cruce subterráneo provisional solicitado por el cliente. Salida al otro lado de la plataforma viaria; cotas, profundidad, soportes y conexión final pendientes del plano definitivo. No para construcción ni cantidades de obra."}; RevisionDocumentalComplementaria: {"fecha": "2026-09-09", "estado": "Revisión documental; geometría conservada", "criterio": "Documentación complementaria recibida el 09/09/2026. Tuberías: paquete actualizado el 07/08; fechas y revisiones por plano. La recepción no cambia la fecha de diseño. Se mantienen cargas del 25/08 y cimentaciones recibidas el 04/09 frente a las versiones anteriores incluidas.", "documentos": ["SOPC-PROCESS_013", "SOPC-PROCESS_016", "SOPC-BACKUP_012"], "conclusiones": ["Se recibieron plantas, isométricos y tablas de líneas de proceso y reserva. Las plantas revisadas son proyecciones 2D; no contienen una red 3D importable. No se ha validado en estas fuentes el cruce exterior solicitado por el cliente ni sus diámetros aproximados de 0,50 y 0,20 m; se mantiene el trazado provisional actual."]}; IncidenciasPendientes: ["Cruce subterráneo provisional solicitado por el cliente. Salida al otro lado de la plataforma viaria; cotas, profundidad, soportes y conexión final pendientes del plano definitivo. No para construcción ni cantidades de obra.", "Se recibieron plantas, isométricos y tablas de líneas de proceso y reserva. Las plantas revisadas son proyecciones 2D; no contienen una red 3D importable. No se ha validado en estas fuentes el cruce exterior solicitado por el cliente ni sus diámetros aproximados de 0,50 y 0,20 m; se mantiene el trazado provisional actual."]
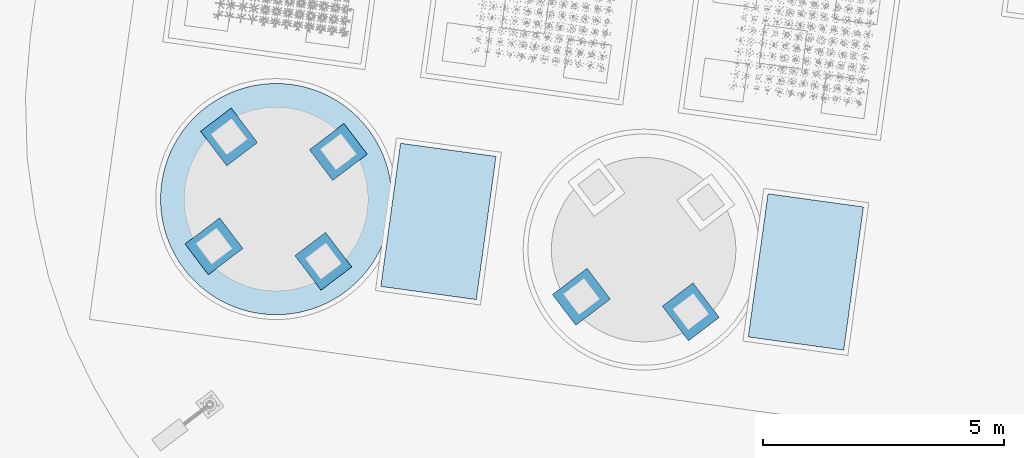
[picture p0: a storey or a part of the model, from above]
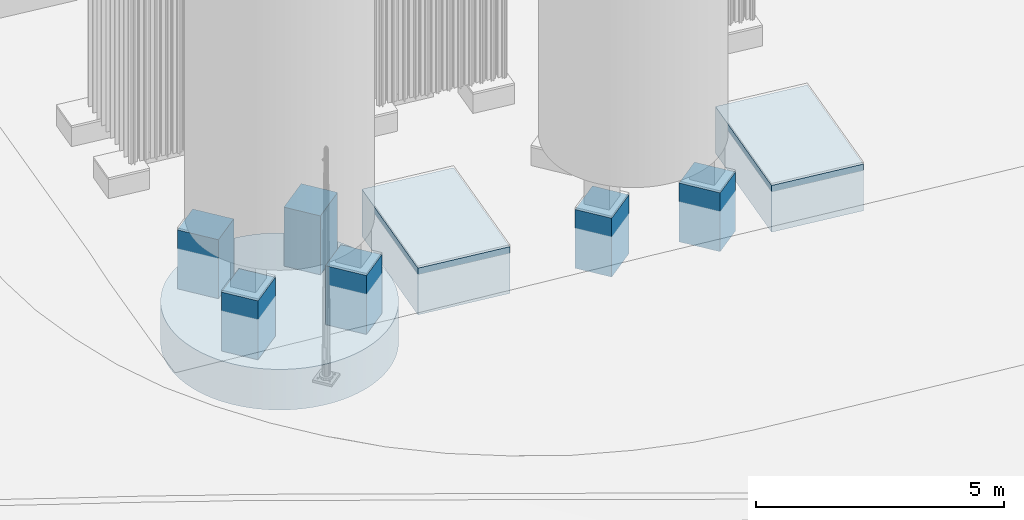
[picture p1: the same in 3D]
Properties of the parts of a building model (IFC4), part 97 of 134

# IfcPipeSegment: Nitrógeno Ø 0,2 m · tramo enterrado
JH_Trazabilidad - Origen: Corrección del cliente · cruce subterráneo completo del vial exterior; Estado: Provisional · no para construcción; Capa BIM: Nitrógeno · tramo enterrado; Mediciones de obra: Excluido; Identificador: N2-200-BURIED; Categoria: Nitrógeno Ø 0,2 m · tramo enterrado; ClaseIFC: IfcPipeSegment; EstadoDeInformacion: provisional; DocumentoFuente: {"documentId":"JH-USER-CROSSING-20260909","title":"Corrección del cliente · cruce subterráneo completo del vial exterior","date":"2026-09-09","sheet":"Croquis rojo sobre el visor con entorno","note":"Entrar al subsuelo dentro de la parcela, atravesar calzada y aceras, y salir al otro lado. Geometría provisional de coordinación; diámetros aproximados 0,50 y 0,20 m."}; IncidenciasPendientes: ["Cruce subterráneo provisional solicitado por el cliente. Salida al otro lado de la plataforma viaria; cotas, profundidad, soportes y conexión final pendientes del plano definitivo. No para construcción ni cantidades de obra.", "Se recibieron plantas, isométricos y tablas de líneas de proceso y reserva. Las plantas revisadas son proyecciones 2D; no contienen una red 3D importable. No se ha validado en estas fuentes el cruce exterior solicitado por el cliente ni sus diámetros aproximados de 0,50 y 0,20 m; se mantiene el trazado provisional actual."]; UsoDeLasMagnitudes: Cruce subterráneo provisional solicitado por el cliente. Salida al otro lado de la plataforma viaria; cotas, profundidad, soportes y conexión final pendientes del plano definitivo. No para construcción ni cantidades de obra.; RevisionDocumentalComplementaria: {"fecha": "2026-09-09", "estado": "Revisión documental; geometría conservada", "criterio": "Documentación complementaria recibida el 09/09/2026. Tuberías: paquete actualizado el 07/08; fechas y revisiones por plano. La recepción no cambia la fecha de diseño. Se mantienen cargas del 25/08 y cimentaciones recibidas el 04/09 frente a las versiones anteriores incluidas.", "documentos": ["SOPC-PROCESS_013", "SOPC-PROCESS_016", "SOPC-BACKUP_012"], "conclusiones": ["Se recibieron plantas, isométricos y tablas de líneas de proceso y reserva. Las plantas revisadas son proyecciones 2D; no contienen una red 3D importable. No se ha validado en estas fuentes el cruce exterior solicitado por el cliente ni sus diámetros aproximados de 0,50 y 0,20 m; se mantiene el trazado provisional actual."]}
JH_CriterioDePosicion - PosicionYEstado: {"Recorrido":"Bajante dentro de la parcela, cruce de toda la calzada y ambas aceras, subida en el margen opuesto.","Salida":"Eje situado aproximadamente 3 m después del borde exterior de la acera opuesta.","Cotas":"Superficie de contexto simplificada; profundidad de visualización, no cálculo de diseño.","Dimensiones":"Diámetros y radios provisionales; conservar hasta recibir plano."}
JH_EvidenciaDeMaterial - name: Tubería de nitrógeno · azul de identificación; status: provisional; source: Material, espesor, aislamiento y protección pendientes de ingeniería.
JH_RevisionDocumental20260909 - Criterio: Documentación complementaria recibida el 09/09/2026. Tuberías: paquete actualizado el 07/08; fechas y revisiones por plano. La recepción no cambia la fecha de diseño. Se mantienen cargas del 25/08 y cimentaciones recibidas el 04/09 frente a las versiones anteriores incluidas.; Documentos: SOPC-PROCESS_013 | SOPC-PROCESS_016 | SOPC-BACKUP_012; Conclusiones: Se recibieron plantas, isométricos y tablas de líneas de proceso y reserva. Las plantas revisadas son proyecciones 2D; no contienen una red 3D importable. No se ha validado en estas fuentes el cruce exterior solicitado por el cliente ni sus diámetros aproximados de 0,50 y 0,20 m; se mantiene el trazado provisional actual.; GeometriaModificada: no

# IfcPipeSegment: Nitrógeno Ø 0,5 m · salida exterior
In: Parcela industrial Jinhong
Description: Cruce subterráneo provisional solicitado por el cliente. Salida al otro lado de la plataforma viaria; cotas, profundidad, soportes y conexión final pendientes del plano definitivo. No para construcción ni cantidades de obra.; PredefinedType: USERDEFINED; Document: Indicación del cliente y croquis sobre el visor · 08/09/2026; Corrección del cliente · cruce subterráneo completo del vial exterior; Planta general de tuberías de proceso; Isométricos de proceso; Plantas de tuberías de reserva; Group: BIM · Galería de nitrógeno · esquema
JH_CapaBIM - IdentificadorCapa: pipe_gallery; NombreCapa: Galería de nitrógeno · esquema; Funcion: Nitrógeno Ø 0,5 m · salida exterior; VisibilidadInicial: yes
JH_EsquemaProvisional - Estado: No para construcción; Origen: {"documentId":"JH-USER-CROSSING-20260909","title":"Corrección del cliente · cruce subterráneo completo del vial exterior","date":"2026-09-09","sheet":"Croquis rojo sobre el visor con entorno","note":"Entrar al subsuelo dentro de la parcela, atravesar calzada y aceras, y salir al otro lado. Geometría provisional de coordinación; diámetros aproximados 0,50 y 0,20 m."}; DimensionesSupuestas: [{"label":"Diámetro exterior aproximado","value":0.5,"unit":"m"},{"label":"Radio orientativo del codo","value":1,"unit":"m"},{"label":"Cruce de calzada y aceras en planta","value":23.403,"unit":"m"},{"label":"Retiro del eje tras la acera opuesta","value":3,"unit":"m"},{"label":"Cota del eje enterrado respecto al origen","value":-0.6741,"unit":"m"},{"label":"Altura de salida sobre el terreno orientativo","value":3,"unit":"m"}]; Posicion: {"Recorrido":"Bajante dentro de la parcela, cruce de toda la calzada y ambas aceras, subida en el margen opuesto.","Salida":"Eje situado aproximadamente 3 m después del borde exterior de la acera opuesta.","Cotas":"Superficie de contexto simplificada; profundidad de visualización, no cálculo de diseño.","Dimensiones":"Diámetros y radios provisionales; conservar hasta recibir plano."}; IncluirEnMediciones: no; Criterio: {"enabled":true,"basis":"Cruce subterráneo provisional solicitado por el cliente. Salida al otro lado de la plataforma viaria; cotas, profundidad, soportes y conexión final pendientes del plano definitivo. No para construcción ni cantidades de obra.","pending":["Plano definitivo de cruce","Profundidad y servicios enterrados","Protección y apoyos","Destino y conexión"]}
JH_TuberiaNitrogeno - Fluido: Nitrógeno; DiametroExteriorOrientativoM: 0.5; EjeRepresentadoM: [[51.976556,-13.888987,0.917728],[51.976556,-13.888987,2.917728],[51.975901,-13.893757,3.015746],[51.973939,-13.908023,3.112819],[51.970692,-13.931645,3.208013],[51.966189,-13.964398,3.300412],[51.960474,-14.005965,3.389125],[51.953602,-14.055947,3.473299],[51.94564,-14.113861,3.552122],[51.936663,-14.179151,3.624835],[51.926759,-14.251186,3.690739],[51.916023,-14.329275,3.749198],[51.904559,-14.412664,3.79965],[51.892476,-14.500551,3.841608],[51.87989,-14.592088,3.874669],[51.866925,-14.686395,3.898514],[51.853703,-14.782564,3.912913],[51.840353,-14.879668,3.917728],[51.636047,-16.365689,3.917728]]; Tramo: OUTLET; Enterrado: no; ClasePresionEspesorYUniones: Pendientes de ingeniería
JH_InformacionBIM - buildingId: site; buildingName: Urbanización y parcela; level: Exterior · esquema de servicios; category: Nitrógeno Ø 0,5 m · salida exterior; ifcClass: IfcPipeSegment; status: provisional; source: {"documentId":"JH-USER-CROSSING-20260909","title":"Corrección del cliente · cruce subterráneo completo del vial exterior","date":"2026-09-09","sheet":"Croquis rojo sobre el visor con entorno","note":"Entrar al subsuelo dentro de la parcela, atravesar calzada y aceras, y salir al otro lado. Geometría provisional de coordinación; diámetros aproximados 0,50 y 0,20 m."}; material: {"name":"Tubería de nitrógeno · acabado claro","status":"provisional","source":"Material, espesor, aislamiento y protección pendientes de ingeniería."}; dimensions: {"documented":[],"assumed":[{"label":"Diámetro exterior aproximado","value":0.5,"unit":"m"},{"label":"Radio orientativo del codo","value":1,"unit":"m"},{"label":"Cruce de calzada y aceras en planta","value":23.403,"unit":"m"},{"label":"Retiro del eje tras la acera opuesta","value":3,"unit":"m"},{"label":"Cota del eje enterrado respecto al origen","value":-0.6741,"unit":"m"},{"label":"Altura de salida sobre el terreno orientativo","value":3,"unit":"m"}],"geometry":[{"label":"Extensión representada X","value":0.836224,"unit":"m"},{"label":"Extensión representada Y","value":2.758797,"unit":"m"},{"label":"Extensión representada Z","value":3.25,"unit":"m"}]}; appearance: {"profileId":"n2_pipe_large","name":"Tubería de nitrógeno · acabado claro","status":"criterio_visual","basis":"Color y acabado orientativos para distinguir el esquema solicitado; material sin especificación confirmada."}; classification: {"layerId":"pipe_gallery","layerName":"Galería de nitrógeno · esquema","function":"Nitrógeno Ø 0,5 m · salida exterior"}; visualLayer: {"id":"pipe_gallery","name":"Galería de nitrógeno · esquema","defaultVisible":true}; representationKind: esquema_provisional_no_constructivo; conceptual: {"enabled":true,"basis":"Cruce subterráneo provisional solicitado por el cliente. Salida al otro lado de la plataforma viaria; cotas, profundidad, soportes y conexión final pendientes del plano definitivo. No para construcción ni cantidades de obra.","pending":["Plano definitivo de cruce","Profundidad y servicios enterrados","Protección y apoyos","Destino y conexión"]}; positioning: {"Recorrido":"Bajante dentro de la parcela, cruce de toda la calzada y ambas aceras, subida en el margen opuesto.","Salida":"Eje situado aproximadamente 3 m después del borde exterior de la acera opuesta.","Cotas":"Superficie de contexto simplificada; profundidad de visualización, no cálculo de diseño.","Dimensiones":"Diámetros y radios provisionales; conservar hasta recibir plano."}; quantityEligible: no; issues: ["Cruce subterráneo provisional solicitado por el cliente. Salida al otro lado de la plataforma viaria; cotas, profundidad, soportes y conexión final pendientes del plano definitivo. No para construcción ni cantidades de obra."]; medium: Nitrógeno; assemblyId: N2-500; pipeDiameterM: 0.5; pipeCenterlineModelM: [[51.976556,-13.888987,0.917728],[51.976556,-13.888987,2.917728],[51.975901,-13.893757,3.015746],[51.973939,-13.908023,3.112819],[51.970692,-13.931645,3.208013],[51.966189,-13.964398,3.300412],[51.960474,-14.005965,3.389125],[51.953602,-14.055947,3.473299],[51.94564,-14.113861,3.552122],[51.936663,-14.179151,3.624835],[51.926759,-14.251186,3.690739],[51.916023,-14.329275,3.749198],[51.904559,-14.412664,3.79965],[51.892476,-14.500551,3.841608],[51.87989,-14.592088,3.874669],[51.866925,-14.686395,3.898514],[51.853703,-14.782564,3.912913],[51.840353,-14.879668,3.917728],[51.636047,-16.365689,3.917728]]; isUnderground: no; pipePhase: OUTLET; connectionsStatus: Bocas representadas por cierre gráfico; no son tapas o uniones de fabricación.; geometryMetrics: {"boundingBoxM":{"min":[51.388377,-16.39974,0.917728],"max":[52.224601,-13.640943,4.167728]},"extentsM":[0.836224,2.758797,3.25],"meshSurfaceM2":8.328227,"meshVolumeM3":0.983826,"closedSolid":true,"basis":"Cruce subterráneo provisional solicitado por el cliente. Salida al otro lado de la plataforma viaria; cotas, profundidad, soportes y conexión final pendientes del plano definitivo. No para construcción ni cantidades de obra."}; RevisionDocumentalComplementaria: {"fecha": "2026-09-09", "estado": "Revisión documental; geometría conservada", "criterio": "Documentación complementaria recibida el 09/09/2026. Tuberías: paquete actualizado el 07/08; fechas y revisiones por plano. La recepción no cambia la fecha de diseño. Se mantienen cargas del 25/08 y cimentaciones recibidas el 04/09 frente a las versiones anteriores incluidas.", "documentos": ["SOPC-PROCESS_013", "SOPC-PROCESS_016", "SOPC-BACKUP_012"], "conclusiones": ["Se recibieron plantas, isométricos y tablas de líneas de proceso y reserva. Las plantas revisadas son proyecciones 2D; no contienen una red 3D importable. No se ha validado en estas fuentes el cruce exterior solicitado por el cliente ni sus diámetros aproximados de 0,50 y 0,20 m; se mantiene el trazado provisional actual."]}; IncidenciasPendientes: ["Cruce subterráneo provisional solicitado por el cliente. Salida al otro lado de la plataforma viaria; cotas, profundidad, soportes y conexión final pendientes del plano definitivo. No para construcción ni cantidades de obra.", "Se recibieron plantas, isométricos y tablas de líneas de proceso y reserva. Las plantas revisadas son proyecciones 2D; no contienen una red 3D importable. No se ha validado en estas fuentes el cruce exterior solicitado por el cliente ni sus diámetros aproximados de 0,50 y 0,20 m; se mantiene el trazado provisional actual."]
JH_Trazabilidad - Origen: Corrección del cliente · cruce subterráneo completo del vial exterior; Estado: Provisional · no para construcción; Capa BIM: Galería de nitrógeno · esquema; Mediciones de obra: Excluido; Identificador: N2-500-OUTLET; Categoria: Nitrógeno Ø 0,5 m · salida exterior; ClaseIFC: IfcPipeSegment; EstadoDeInformacion: provisional; DocumentoFuente: {"documentId":"JH-USER-CROSSING-20260909","title":"Corrección del cliente · cruce subterráneo completo del vial exterior","date":"2026-09-09","sheet":"Croquis rojo sobre el visor con entorno","note":"Entrar al subsuelo dentro de la parcela, atravesar calzada y aceras, y salir al otro lado. Geometría provisional de coordinación; diámetros aproximados 0,50 y 0,20 m."}; IncidenciasPendientes: ["Cruce subterráneo provisional solicitado por el cliente. Salida al otro lado de la plataforma viaria; cotas, profundidad, soportes y conexión final pendientes del plano definitivo. No para construcción ni cantidades de obra.", "Se recibieron plantas, isométricos y tablas de líneas de proceso y reserva. Las plantas revisadas son proyecciones 2D; no contienen una red 3D importable. No se ha validado en estas fuentes el cruce exterior solicitado por el cliente ni sus diámetros aproximados de 0,50 y 0,20 m; se mantiene el trazado provisional actual."]; UsoDeLasMagnitudes: Cruce subterráneo provisional solicitado por el cliente. Salida al otro lado de la plataforma viaria; cotas, profundidad, soportes y conexión final pendientes del plano definitivo. No para construcción ni cantidades de obra.; RevisionDocumentalComplementaria: {"fecha": "2026-09-09", "estado": "Revisión documental; geometría conservada", "criterio": "Documentación complementaria recibida el 09/09/2026. Tuberías: paquete actualizado el 07/08; fechas y revisiones por plano. La recepción no cambia la fecha de diseño. Se mantienen cargas del 25/08 y cimentaciones recibidas el 04/09 frente a las versiones anteriores incluidas.", "documentos": ["SOPC-PROCESS_013", "SOPC-PROCESS_016", "SOPC-BACKUP_012"], "conclusiones": ["Se recibieron plantas, isométricos y tablas de líneas de proceso y reserva. Las plantas revisadas son proyecciones 2D; no contienen una red 3D importable. No se ha validado en estas fuentes el cruce exterior solicitado por el cliente ni sus diámetros aproximados de 0,50 y 0,20 m; se mantiene el trazado provisional actual."]}
JH_CriterioDePosicion - PosicionYEstado: {"Recorrido":"Bajante dentro de la parcela, cruce de toda la calzada y ambas aceras, subida en el margen opuesto.","Salida":"Eje situado aproximadamente 3 m después del borde exterior de la acera opuesta.","Cotas":"Superficie de contexto simplificada; profundidad de visualización, no cálculo de diseño.","Dimensiones":"Diámetros y radios provisionales; conservar hasta recibir plano."}
JH_EvidenciaDeMaterial - name: Tubería de nitrógeno · acabado claro; status: provisional; source: Material, espesor, aislamiento y protección pendientes de ingeniería.
JH_RevisionDocumental20260909 - Criterio: Documentación complementaria recibida el 09/09/2026. Tuberías: paquete actualizado el 07/08; fechas y revisiones por plano. La recepción no cambia la fecha de diseño. Se mantienen cargas del 25/08 y cimentaciones recibidas el 04/09 frente a las versiones anteriores incluidas.; Documentos: SOPC-PROCESS_013 | SOPC-PROCESS_016 | SOPC-BACKUP_012; Conclusiones: Se recibieron plantas, isométricos y tablas de líneas de proceso y reserva. Las plantas revisadas son proyecciones 2D; no contienen una red 3D importable. No se ha validado en estas fuentes el cruce exterior solicitado por el cliente ni sus diámetros aproximados de 0,50 y 0,20 m; se mantiene el trazado provisional actual.; GeometriaModificada: no

# IfcPipeSegment: Nitrógeno Ø 0,5 m · tramo aéreo y bajante
In: Parcela industrial Jinhong
Description: Cruce subterráneo provisional solicitado por el cliente. Salida al otro lado de la plataforma viaria; cotas, profundidad, soportes y conexión final pendientes del plano definitivo. No para construcción ni cantidades de obra.; PredefinedType: USERDEFINED; Document: Indicación del cliente y croquis sobre el visor · 08/09/2026; Corrección del cliente · cruce subterráneo completo del vial exterior; Planta general de tuberías de proceso; Isométricos de proceso; Plantas de tuberías de reserva; Group: BIM · Galería de nitrógeno · esquema
JH_CapaBIM - IdentificadorCapa: pipe_gallery; NombreCapa: Galería de nitrógeno · esquema; Funcion: Nitrógeno Ø 0,5 m · tramo aéreo y bajante; VisibilidadInicial: yes
JH_EsquemaProvisional - Estado: No para construcción; Origen: {"documentId":"JH-USER-N2-20260908","title":"Indicación del cliente y croquis sobre el visor · 08/09/2026","date":"2026-09-08","sheet":"Recorrido orientativo señalado en rojo","note":"Diámetros aproximados de 0,50 y 0,20 m solicitados por el cliente. No es un plano de ingeniería."}; DimensionesSupuestas: [{"label":"Diámetro exterior aproximado solicitado","value":0.5,"unit":"m"},{"label":"Separación transversal entre ejes","value":0.9,"unit":"m"},{"label":"Radio orientativo de codos","value":1.0,"unit":"m"},{"label":"Cota del eje aéreo respecto al origen del modelo","value":7.2,"unit":"m"},{"label":"Profundidad orientativa del eje enterrado","value":1.5,"unit":"m"},{"label":"Representación","value":"Envolvente maciza de visualización; espesor de pared y aislamiento no definidos","unit":""}]; Posicion: {"Trazado":"Desde el entorno de la caja fría hacia el borde sur indicado en el croquis; entrada al subsuelo dentro de la parcela.","Entrada al subsuelo":"Eje aproximado a 1,19 m del lindero; dos tuberías desplazadas ±0,45 m lateralmente.","Terreno exterior":"Nivel provisional prolongado desde la entrada al subsuelo; no se aporta levantamiento exterior ni se amplía la parcela."}; IncluirEnMediciones: no; Criterio: {"enabled":true,"basis":"Esquema provisional solicitado por el cliente. Trazado, altura, profundidad, soportes, material y conexiones pendientes de plano; no para construcción ni cómputo de cantidades.","pending":["Plano de ruta y servidumbre exterior","Alturas, profundidad y recubrimiento","Clase de tubería, presión, espesor, aislamiento y uniones","Cálculo de soportes, dilatación y conexiones reales"]}
JH_TuberiaNitrogeno - Fluido: Nitrógeno; DiametroExteriorOrientativoM: 0.5; EjeRepresentadoM: [[59.445806,40.438708,7.2],[55.870455,14.433337,7.2],[55.857104,14.336233,7.195185],[55.843883,14.240064,7.180785],[55.830917,14.145757,7.15694],[55.818332,14.054219,7.12388],[55.806249,13.966333,7.081921],[55.794784,13.882944,7.03147],[55.784048,13.804855,6.97301],[55.774144,13.732819,6.907107],[55.765168,13.66753,6.834393],[55.757205,13.609616,6.75557],[55.750334,13.559634,6.671397],[55.744619,13.518067,6.582683],[55.740116,13.485314,6.490285],[55.736868,13.461691,6.39509],[55.734907,13.447426,6.298017],[55.734251,13.442656,6.2],[55.734251,13.442656,1.261512]]; Tramo: AERIAL; Enterrado: no; ClasePresionEspesorYUniones: Pendientes de ingeniería
JH_InformacionBIM - buildingId: site; buildingName: Urbanización y parcela; level: Exterior · esquema de servicios; category: Nitrógeno Ø 0,5 m · tramo aéreo y bajante; ifcClass: IfcPipeSegment; status: provisional; source: {"documentId":"JH-USER-CROSSING-20260909","title":"Corrección del cliente · cruce subterráneo completo del vial exterior","date":"2026-09-09","sheet":"Croquis rojo sobre el visor con entorno","note":"Entrar al subsuelo dentro de la parcela, atravesar calzada y aceras, y salir al otro lado. Geometría provisional de coordinación; diámetros aproximados 0,50 y 0,20 m."}; material: {"name":"Tubería de nitrógeno · acabado claro","status":"provisional","source":"Material, espesor, aislamiento y protección pendientes de ingeniería."}; dimensions: {"documented":[],"assumed":[{"label":"Diámetro exterior aproximado solicitado","value":0.5,"unit":"m"},{"label":"Separación transversal entre ejes","value":0.9,"unit":"m"},{"label":"Radio orientativo de codos","value":1.0,"unit":"m"},{"label":"Cota del eje aéreo respecto al origen del modelo","value":7.2,"unit":"m"},{"label":"Profundidad del eje enterrado bajo la entrada adoptada","value":1.935608,"unit":"m"},{"label":"Representación","value":"Envolvente maciza de visualización; espesor de pared y aislamiento no definidos","unit":""}],"geometry":[{"label":"Extensión representada X","value":4.20727,"unit":"m"},{"label":"Extensión representada Y","value":27.278147,"unit":"m"},{"label":"Extensión representada Z","value":6.188488,"unit":"m"}]}; appearance: {"profileId":"n2_pipe_large","name":"Tubería de nitrógeno · acabado claro","status":"criterio_visual","basis":"Color y acabado orientativos para distinguir el esquema solicitado; material sin especificación confirmada."}; classification: {"layerId":"pipe_gallery","layerName":"Galería de nitrógeno · esquema","function":"Nitrógeno Ø 0,5 m · tramo aéreo y bajante"}; visualLayer: {"id":"pipe_gallery","name":"Galería de nitrógeno · esquema","defaultVisible":true}; representationKind: esquema_provisional_no_constructivo; conceptual: {"enabled":true,"basis":"Esquema provisional solicitado por el cliente. Trazado, altura, profundidad, soportes, material y conexiones pendientes de plano; no para construcción ni cómputo de cantidades.","pending":["Plano de ruta y servidumbre exterior","Alturas, profundidad y recubrimiento","Clase de tubería, presión, espesor, aislamiento y uniones","Cálculo de soportes, dilatación y conexiones reales"]}; positioning: {"Trazado":"Desde el entorno de la caja fría hacia el borde sur indicado en el croquis; entrada al subsuelo dentro de la parcela.","Entrada al subsuelo":"Eje aproximado a 1,19 m del lindero; dos tuberías desplazadas ±0,45 m lateralmente.","Terreno exterior":"Nivel provisional prolongado desde la entrada al subsuelo; no se aporta levantamiento exterior ni se amplía la parcela."}; quantityEligible: no; issues: ["Esquema provisional solicitado por el cliente. Trazado, altura, profundidad, soportes, material y conexiones pendientes de plano; no para construcción ni cómputo de cantidades.","La posición de la salida exterior y el terreno de contexto son orientativos, sin confirmar propiedad, permisos ni destino de conexión."]; medium: Nitrógeno; assemblyId: N2-500; pipeDiameterM: 0.5; pipeCenterlineModelM: [[59.445806,40.438708,7.2],[55.870455,14.433337,7.2],[55.857104,14.336233,7.195185],[55.843883,14.240064,7.180785],[55.830917,14.145757,7.15694],[55.818332,14.054219,7.12388],[55.806249,13.966333,7.081921],[55.794784,13.882944,7.03147],[55.784048,13.804855,6.97301],[55.774144,13.732819,6.907107],[55.765168,13.66753,6.834393],[55.757205,13.609616,6.75557],[55.750334,13.559634,6.671397],[55.744619,13.518067,6.582683],[55.740116,13.485314,6.490285],[55.736868,13.461691,6.39509],[55.734907,13.447426,6.298017],[55.734251,13.442656,6.2],[55.734251,13.442656,1.261512]]; isUnderground: no; pipePhase: AERIAL; connectionsStatus: Bocas representadas por cierre gráfico; no son tapas o uniones de fabricación.; geometryMetrics: {"boundingBoxM":{"min":[55.486207,13.194612,1.261512],"max":[59.693477,40.472759,7.45]},"extentsM":[4.20727,27.278147,6.188488],"meshSurfaceM2":51.697075,"meshVolumeM3":6.35855,"closedSolid":true,"basis":"Esquema provisional de coordinación autorizado por el cliente. Tuberías, soportes, alumbrado e hidrantes con dimensiones y posiciones orientativas; no para construcción ni cómputo de cantidades."}; crossingReference: {"documentId":"JH-USER-CROSSING-20260909","title":"Corrección del cliente · cruce subterráneo completo del vial exterior","date":"2026-09-09","sheet":"Croquis rojo sobre el visor con entorno","note":"Entrar al subsuelo dentro de la parcela, atravesar calzada y aceras, y salir al otro lado. Geometría provisional de coordinación; diámetros aproximados 0,50 y 0,20 m."}; RevisionDocumentalComplementaria: {"fecha": "2026-09-09", "estado": "Revisión documental; geometría conservada", "criterio": "Documentación complementaria recibida el 09/09/2026. Tuberías: paquete actualizado el 07/08; fechas y revisiones por plano. La recepción no cambia la fecha de diseño. Se mantienen cargas del 25/08 y cimentaciones recibidas el 04/09 frente a las versiones anteriores incluidas.", "documentos": ["SOPC-PROCESS_013", "SOPC-PROCESS_016", "SOPC-BACKUP_012"], "conclusiones": ["Se recibieron plantas, isométricos y tablas de líneas de proceso y reserva. Las plantas revisadas son proyecciones 2D; no contienen una red 3D importable. No se ha validado en estas fuentes el cruce exterior solicitado por el cliente ni sus diámetros aproximados de 0,50 y 0,20 m; se mantiene el trazado provisional actual."]}; IncidenciasPendientes: ["Esquema provisional solicitado por el cliente. Trazado, altura, profundidad, soportes, material y conexiones pendientes de plano; no para construcción ni cómputo de cantidades.", "La posición de la salida exterior y el terreno de contexto son orientativos, sin confirmar propiedad, permisos ni destino de conexión.", "Se recibieron plantas, isométricos y tablas de líneas de proceso y reserva. Las plantas revisadas son proyecciones 2D; no contienen una red 3D importable. No se ha validado en estas fuentes el cruce exterior solicitado por el cliente ni sus diámetros aproximados de 0,50 y 0,20 m; se mantiene el trazado provisional actual."]
JH_Trazabilidad - Origen: Corrección del cliente · cruce subterráneo completo del vial exterior; Estado: Provisional · no para construcción; Capa BIM: Galería de nitrógeno · esquema; Mediciones de obra: Excluido; Identificador: N2-500-AERIAL; Categoria: Nitrógeno Ø 0,5 m · tramo aéreo y bajante; ClaseIFC: IfcPipeSegment; EstadoDeInformacion: provisional; DocumentoFuente: {"documentId":"JH-USER-CROSSING-20260909","title":"Corrección del cliente · cruce subterráneo completo del vial exterior","date":"2026-09-09","sheet":"Croquis rojo sobre el visor con entorno","note":"Entrar al subsuelo dentro de la parcela, atravesar calzada y aceras, y salir al otro lado. Geometría provisional de coordinación; diámetros aproximados 0,50 y 0,20 m."}; IncidenciasPendientes: ["Esquema provisional solicitado por el cliente. Trazado, altura, profundidad, soportes, material y conexiones pendientes de plano; no para construcción ni cómputo de cantidades.", "La posición de la salida exterior y el terreno de contexto son orientativos, sin confirmar propiedad, permisos ni destino de conexión.", "Se recibieron plantas, isométricos y tablas de líneas de proceso y reserva. Las plantas revisadas son proyecciones 2D; no contienen una red 3D importable. No se ha validado en estas fuentes el cruce exterior solicitado por el cliente ni sus diámetros aproximados de 0,50 y 0,20 m; se mantiene el trazado provisional actual."]; UsoDeLasMagnitudes: Cruce subterráneo provisional solicitado por el cliente. Salida al otro lado de la plataforma viaria; cotas, profundidad, soportes y conexión final pendientes del plano definitivo. No para construcción ni cantidades de obra.; RevisionDocumentalComplementaria: {"fecha": "2026-09-09", "estado": "Revisión documental; geometría conservada", "criterio": "Documentación complementaria recibida el 09/09/2026. Tuberías: paquete actualizado el 07/08; fechas y revisiones por plano. La recepción no cambia la fecha de diseño. Se mantienen cargas del 25/08 y cimentaciones recibidas el 04/09 frente a las versiones anteriores incluidas.", "documentos": ["SOPC-PROCESS_013", "SOPC-PROCESS_016", "SOPC-BACKUP_012"], "conclusiones": ["Se recibieron plantas, isométricos y tablas de líneas de proceso y reserva. Las plantas revisadas son proyecciones 2D; no contienen una red 3D importable. No se ha validado en estas fuentes el cruce exterior solicitado por el cliente ni sus diámetros aproximados de 0,50 y 0,20 m; se mantiene el trazado provisional actual."]}
JH_CriterioDePosicion - PosicionYEstado: {"Trazado":"Desde el entorno de la caja fría hacia el borde sur indicado en el croquis; entrada al subsuelo dentro de la parcela.","Entrada al subsuelo":"Eje aproximado a 1,19 m del lindero; dos tuberías desplazadas ±0,45 m lateralmente.","Terreno exterior":"Nivel provisional prolongado desde la entrada al subsuelo; no se aporta levantamiento exterior ni se amplía la parcela."}
JH_EvidenciaDeMaterial - name: Tubería de nitrógeno · acabado claro; status: provisional; source: Material, espesor, aislamiento y protección pendientes de ingeniería.
JH_RevisionDocumental20260909 - Criterio: Documentación complementaria recibida el 09/09/2026. Tuberías: paquete actualizado el 07/08; fechas y revisiones por plano. La recepción no cambia la fecha de diseño. Se mantienen cargas del 25/08 y cimentaciones recibidas el 04/09 frente a las versiones anteriores incluidas.; Documentos: SOPC-PROCESS_013 | SOPC-PROCESS_016 | SOPC-BACKUP_012; Conclusiones: Se recibieron plantas, isométricos y tablas de líneas de proceso y reserva. Las plantas revisadas son proyecciones 2D; no contienen una red 3D importable. No se ha validado en estas fuentes el cruce exterior solicitado por el cliente ni sus diámetros aproximados de 0,50 y 0,20 m; se mantiene el trazado provisional actual.; GeometriaModificada: no

# IfcPipeSegment: Nitrógeno Ø 0,5 m · tramo enterrado
In: Parcela industrial Jinhong
Description: Cruce subterráneo provisional solicitado por el cliente. Salida al otro lado de la plataforma viaria; cotas, profundidad, soportes y conexión final pendientes del plano definitivo. No para construcción ni cantidades de obra.; PredefinedType: USERDEFINED; Document: Indicación del cliente y croquis sobre el visor · 08/09/2026; Corrección del cliente · cruce subterráneo completo del vial exterior; Planta general de tuberías de proceso; Isométricos de proceso; Plantas de tuberías de reserva; Group: BIM · Nitrógeno · tramo enterrado
JH_CapaBIM - IdentificadorCapa: pipe_underground; NombreCapa: Nitrógeno · tramo enterrado; Funcion: Nitrógeno Ø 0,5 m · tramo enterrado; VisibilidadInicial: yes
JH_EsquemaProvisional - Estado: No para construcción; Origen: {"documentId":"JH-USER-CROSSING-20260909","title":"Corrección del cliente · cruce subterráneo completo del vial exterior","date":"2026-09-09","sheet":"Croquis rojo sobre el visor con entorno","note":"Entrar al subsuelo dentro de la parcela, atravesar calzada y aceras, y salir al otro lado. Geometría provisional de coordinación; diámetros aproximados 0,50 y 0,20 m."}; DimensionesSupuestas: [{"label":"Diámetro exterior aproximado","value":0.5,"unit":"m"},{"label":"Radio orientativo del codo","value":1,"unit":"m"},{"label":"Cruce de calzada y aceras en planta","value":23.403,"unit":"m"},{"label":"Retiro del eje tras la acera opuesta","value":3,"unit":"m"},{"label":"Cota del eje enterrado respecto al origen","value":-0.6741,"unit":"m"},{"label":"Altura de salida sobre el terreno orientativo","value":3,"unit":"m"}]; Posicion: {"Recorrido":"Bajante dentro de la parcela, cruce de toda la calzada y ambas aceras, subida en el margen opuesto.","Salida":"Eje situado aproximadamente 3 m después del borde exterior de la acera opuesta.","Cotas":"Superficie de contexto simplificada; profundidad de visualización, no cálculo de diseño.","Dimensiones":"Diámetros y radios provisionales; conservar hasta recibir plano."}; IncluirEnMediciones: no; Criterio: {"enabled":true,"basis":"Cruce subterráneo provisional solicitado por el cliente. Salida al otro lado de la plataforma viaria; cotas, profundidad, soportes y conexión final pendientes del plano definitivo. No para construcción ni cantidades de obra.","pending":["Plano definitivo de cruce","Profundidad y servicios enterrados","Protección y apoyos","Destino y conexión"]}
JH_TuberiaNitrogeno - Fluido: Nitrógeno; DiametroExteriorOrientativoM: 0.5; EjeRepresentadoM: [[55.734251,13.442656,1.261512],[55.734251,13.442656,0.325904],[55.733595,13.437885,0.227887],[55.731634,13.42362,0.130814],[55.728386,13.399997,0.03562],[55.723883,13.367245,-0.056779],[55.718168,13.325677,-0.145492],[55.711296,13.275696,-0.229666],[55.703334,13.217781,-0.308489],[55.694358,13.152492,-0.381202],[55.684454,13.080456,-0.447106],[55.673718,13.002368,-0.505565],[55.662253,12.918979,-0.556017],[55.65017,12.831092,-0.597975],[55.637585,12.739554,-0.631036],[55.624619,12.645247,-0.654881],[55.611397,12.549079,-0.66928],[55.598047,12.451975,-0.674096],[52.11276,-12.898306,-0.674096],[52.09941,-12.99541,-0.66928],[52.086188,-13.091578,-0.654881],[52.073222,-13.185886,-0.631036],[52.060637,-13.277423,-0.597975],[52.048554,-13.36531,-0.556017],[52.03709,-13.448699,-0.505565],[52.026354,-13.526787,-0.447106],[52.01645,-13.598823,-0.381202],[52.007473,-13.664113,-0.308489],[51.999511,-13.722027,-0.229666],[51.992639,-13.772009,-0.145492],[51.986924,-13.813576,-0.056779],[51.982421,-13.846328,0.03562],[51.979174,-13.869951,0.130814],[51.977212,-13.884216,0.227887],[51.976556,-13.888987,0.325904],[51.976556,-13.888987,0.917728]]; Tramo: BURIED; Enterrado: yes; ClasePresionEspesorYUniones: Pendientes de ingeniería
JH_InformacionBIM - buildingId: site; buildingName: Urbanización y parcela; level: Exterior · esquema de servicios; category: Nitrógeno Ø 0,5 m · tramo enterrado; ifcClass: IfcPipeSegment; status: provisional; source: {"documentId":"JH-USER-CROSSING-20260909","title":"Corrección del cliente · cruce subterráneo completo del vial exterior","date":"2026-09-09","sheet":"Croquis rojo sobre el visor con entorno","note":"Entrar al subsuelo dentro de la parcela, atravesar calzada y aceras, y salir al otro lado. Geometría provisional de coordinación; diámetros aproximados 0,50 y 0,20 m."}; material: {"name":"Tubería de nitrógeno · acabado claro","status":"provisional","source":"Material, espesor, aislamiento y protección pendientes de ingeniería."}; dimensions: {"documented":[],"assumed":[{"label":"Diámetro exterior aproximado","value":0.5,"unit":"m"},{"label":"Radio orientativo del codo","value":1,"unit":"m"},{"label":"Cruce de calzada y aceras en planta","value":23.403,"unit":"m"},{"label":"Retiro del eje tras la acera opuesta","value":3,"unit":"m"},{"label":"Cota del eje enterrado respecto al origen","value":-0.6741,"unit":"m"},{"label":"Altura de salida sobre el terreno orientativo","value":3,"unit":"m"}],"geometry":[{"label":"Extensión representada X","value":4.253783,"unit":"m"},{"label":"Extensión representada Y","value":27.827731,"unit":"m"},{"label":"Extensión representada Z","value":2.185608,"unit":"m"}]}; appearance: {"profileId":"n2_pipe_large","name":"Tubería de nitrógeno · acabado claro","status":"criterio_visual","basis":"Color y acabado orientativos para distinguir el esquema solicitado; material sin especificación confirmada."}; classification: {"layerId":"pipe_underground","layerName":"Nitrógeno · tramo enterrado","function":"Nitrógeno Ø 0,5 m · tramo enterrado"}; visualLayer: {"id":"pipe_underground","name":"Nitrógeno · tramo enterrado","defaultVisible":true}; representationKind: esquema_provisional_no_constructivo; conceptual: {"enabled":true,"basis":"Cruce subterráneo provisional solicitado por el cliente. Salida al otro lado de la plataforma viaria; cotas, profundidad, soportes y conexión final pendientes del plano definitivo. No para construcción ni cantidades de obra.","pending":["Plano definitivo de cruce","Profundidad y servicios enterrados","Protección y apoyos","Destino y conexión"]}; positioning: {"Recorrido":"Bajante dentro de la parcela, cruce de toda la calzada y ambas aceras, subida en el margen opuesto.","Salida":"Eje situado aproximadamente 3 m después del borde exterior de la acera opuesta.","Cotas":"Superficie de contexto simplificada; profundidad de visualización, no cálculo de diseño.","Dimensiones":"Diámetros y radios provisionales; conservar hasta recibir plano."}; quantityEligible: no; issues: ["Cruce subterráneo provisional solicitado por el cliente. Salida al otro lado de la plataforma viaria; cotas, profundidad, soportes y conexión final pendientes del plano definitivo. No para construcción ni cantidades de obra."]; medium: Nitrógeno; assemblyId: N2-500; pipeDiameterM: 0.5; pipeCenterlineModelM: [[55.734251,13.442656,1.261512],[55.734251,13.442656,0.325904],[55.733595,13.437885,0.227887],[55.731634,13.42362,0.130814],[55.728386,13.399997,0.03562],[55.723883,13.367245,-0.056779],[55.718168,13.325677,-0.145492],[55.711296,13.275696,-0.229666],[55.703334,13.217781,-0.308489],[55.694358,13.152492,-0.381202],[55.684454,13.080456,-0.447106],[55.673718,13.002368,-0.505565],[55.662253,12.918979,-0.556017],[55.65017,12.831092,-0.597975],[55.637585,12.739554,-0.631036],[55.624619,12.645247,-0.654881],[55.611397,12.549079,-0.66928],[55.598047,12.451975,-0.674096],[52.11276,-12.898306,-0.674096],[52.09941,-12.99541,-0.66928],[52.086188,-13.091578,-0.654881],[52.073222,-13.185886,-0.631036],[52.060637,-13.277423,-0.597975],[52.048554,-13.36531,-0.556017],[52.03709,-13.448699,-0.505565],[52.026354,-13.526787,-0.447106],[52.01645,-13.598823,-0.381202],[52.007473,-13.664113,-0.308489],[51.999511,-13.722027,-0.229666],[51.992639,-13.772009,-0.145492],[51.986924,-13.813576,-0.056779],[51.982421,-13.846328,0.03562],[51.979174,-13.869951,0.130814],[51.977212,-13.884216,0.227887],[51.976556,-13.888987,0.325904],[51.976556,-13.888987,0.917728]]; isUnderground: yes; pipePhase: BURIED; connectionsStatus: Bocas representadas por cierre gráfico; no son tapas o uniones de fabricación.; geometryMetrics: {"boundingBoxM":{"min":[51.728512,-14.137031,-0.924096],"max":[55.982295,13.6907,1.261512]},"extentsM":[4.253783,27.827731,2.185608],"meshSurfaceM2":47.776483,"meshVolumeM3":5.87249,"closedSolid":true,"basis":"Cruce subterráneo provisional solicitado por el cliente. Salida al otro lado de la plataforma viaria; cotas, profundidad, soportes y conexión final pendientes del plano definitivo. No para construcción ni cantidades de obra."}; RevisionDocumentalComplementaria: {"fecha": "2026-09-09", "estado": "Revisión documental; geometría conservada", "criterio": "Documentación complementaria recibida el 09/09/2026. Tuberías: paquete actualizado el 07/08; fechas y revisiones por plano. La recepción no cambia la fecha de diseño. Se mantienen cargas del 25/08 y cimentaciones recibidas el 04/09 frente a las versiones anteriores incluidas.", "documentos": ["SOPC-PROCESS_013", "SOPC-PROCESS_016", "SOPC-BACKUP_012"], "conclusiones": ["Se recibieron plantas, isométricos y tablas de líneas de proceso y reserva. Las plantas revisadas son proyecciones 2D; no contienen una red 3D importable. No se ha validado en estas fuentes el cruce exterior solicitado por el cliente ni sus diámetros aproximados de 0,50 y 0,20 m; se mantiene el trazado provisional actual."]}; IncidenciasPendientes: ["Cruce subterráneo provisional solicitado por el cliente. Salida al otro lado de la plataforma viaria; cotas, profundidad, soportes y conexión final pendientes del plano definitivo. No para construcción ni cantidades de obra.", "Se recibieron plantas, isométricos y tablas de líneas de proceso y reserva. Las plantas revisadas son proyecciones 2D; no contienen una red 3D importable. No se ha validado en estas fuentes el cruce exterior solicitado por el cliente ni sus diámetros aproximados de 0,50 y 0,20 m; se mantiene el trazado provisional actual."]
JH_Trazabilidad - Origen: Corrección del cliente · cruce subterráneo completo del vial exterior; Estado: Provisional · no para construcción; Capa BIM: Nitrógeno · tramo enterrado; Mediciones de obra: Excluido; Identificador: N2-500-BURIED; Categoria: Nitrógeno Ø 0,5 m · tramo enterrado; ClaseIFC: IfcPipeSegment; EstadoDeInformacion: provisional; DocumentoFuente: {"documentId":"JH-USER-CROSSING-20260909","title":"Corrección del cliente · cruce subterráneo completo del vial exterior","date":"2026-09-09","sheet":"Croquis rojo sobre el visor con entorno","note":"Entrar al subsuelo dentro de la parcela, atravesar calzada y aceras, y salir al otro lado. Geometría provisional de coordinación; diámetros aproximados 0,50 y 0,20 m."}; IncidenciasPendientes: ["Cruce subterráneo provisional solicitado por el cliente. Salida al otro lado de la plataforma viaria; cotas, profundidad, soportes y conexión final pendientes del plano definitivo. No para construcción ni cantidades de obra.", "Se recibieron plantas, isométricos y tablas de líneas de proceso y reserva. Las plantas revisadas son proyecciones 2D; no contienen una red 3D importable. No se ha validado en estas fuentes el cruce exterior solicitado por el cliente ni sus diámetros aproximados de 0,50 y 0,20 m; se mantiene el trazado provisional actual."]; UsoDeLasMagnitudes: Cruce subterráneo provisional solicitado por el cliente. Salida al otro lado de la plataforma viaria; cotas, profundidad, soportes y conexión final pendientes del plano definitivo. No para construcción ni cantidades de obra.; RevisionDocumentalComplementaria: {"fecha": "2026-09-09", "estado": "Revisión documental; geometría conservada", "criterio": "Documentación complementaria recibida el 09/09/2026. Tuberías: paquete actualizado el 07/08; fechas y revisiones por plano. La recepción no cambia la fecha de diseño. Se mantienen cargas del 25/08 y cimentaciones recibidas el 04/09 frente a las versiones anteriores incluidas.", "documentos": ["SOPC-PROCESS_013", "SOPC-PROCESS_016", "SOPC-BACKUP_012"], "conclusiones": ["Se recibieron plantas, isométricos y tablas de líneas de proceso y reserva. Las plantas revisadas son proyecciones 2D; no contienen una red 3D importable. No se ha validado en estas fuentes el cruce exterior solicitado por el cliente ni sus diámetros aproximados de 0,50 y 0,20 m; se mantiene el trazado provisional actual."]}
JH_CriterioDePosicion - PosicionYEstado: {"Recorrido":"Bajante dentro de la parcela, cruce de toda la calzada y ambas aceras, subida en el margen opuesto.","Salida":"Eje situado aproximadamente 3 m después del borde exterior de la acera opuesta.","Cotas":"Superficie de contexto simplificada; profundidad de visualización, no cálculo de diseño.","Dimensiones":"Diámetros y radios provisionales; conservar hasta recibir plano."}
JH_EvidenciaDeMaterial - name: Tubería de nitrógeno · acabado claro; status: provisional; source: Material, espesor, aislamiento y protección pendientes de ingeniería.
JH_RevisionDocumental20260909 - Criterio: Documentación complementaria recibida el 09/09/2026. Tuberías: paquete actualizado el 07/08; fechas y revisiones por plano. La recepción no cambia la fecha de diseño. Se mantienen cargas del 25/08 y cimentaciones recibidas el 04/09 frente a las versiones anteriores incluidas.; Documentos: SOPC-PROCESS_013 | SOPC-PROCESS_016 | SOPC-BACKUP_012; Conclusiones: Se recibieron plantas, isométricos y tablas de líneas de proceso y reserva. Las plantas revisadas son proyecciones 2D; no contienen una red 3D importable. No se ha validado en estas fuentes el cruce exterior solicitado por el cliente ni sus diámetros aproximados de 0,50 y 0,20 m; se mantiene el trazado provisional actual.; GeometriaModificada: no

# IfcPlate: Cimentación industrial (48)
In: Parcela industrial Jinhong
Description: Cimentación industrial; PredefinedType: USERDEFINED; Document: Cimentaciones de equipos y pedestales del fabricante · revisión recibida 04/09/2026; Group: Zona de separación de aire; BIM · Cimentaciones
JH_InformacionBIM - material: {"name":"Acero de placa embebida · grado pendiente de confirmar","status":"Dimensiones documentadas; grado sin confirmar","source":"Detalles MJ-1/MJ-2/M1"}; status: provisional; buildingId: process_plant; buildingName: Zona de separación de aire; category: Cimentación industrial; representationKind: foundation; geometryStatus: Geometría de fabricante; implantación absoluta provisional; ifcClass: IfcPlate; visualLayer: {"id":"foundations","name":"Cimentaciones"}; materialAppearance: {"profileId":"steel_embedded","name":"Placa embebida · acero sin grado confirmado","materialName":"Acero de placa embebida · grado pendiente de confirmar","physicalMaterialStatus":"Dimensiones documentadas; grado sin confirmar","physicalMaterialSource":"Detalles MJ-1/MJ-2/M1","appearanceStatus":"criterio_visual","appearanceBasis":"Interpretación visual del material documental; el acabado, tono y parámetros PBR no son una especificación contractual.","note":"La apariencia gráfica no modifica ni confirma la especificación física del material."}; componentSeparation: {"status":"objeto_independiente","note":"Control de visibilidad del objeto completo; la clasificación no altera la malla."}; classification: {"layerId":"foundations","layerName":"Cimentaciones","role":"Cimentación industrial","basis":"Clasificación por función del elemento; no modifica las especificaciones documentales."}; layerId: foundations; appearance: {"profileId":"steel_embedded","name":"Placa embebida · acero sin grado confirmado","status":"criterio_visual","basis":"Interpretación visual del material documental; el acabado, tono y parámetros PBR no son una especificación contractual.","physicalMaterialUnchanged":true}
JH_Trazabilidad - Documento de origen: Cimentaciones de equipos y pedestales del fabricante · revisión recibida 04/09/2026; Material: Acero de placa embebida · grado pendiente de confirmar; Referencia vertical: Cotas relativas del dibujo. La equivalencia con un datum absoluto está pendiente.; Implantación para visualización: Z del modelo = cota relativa + 1,10 m. Correspondencia provisional con 286,10 m; no es cota de obra confirmada.; Capa BIM: Cimentaciones; Acabado de visualización: Placa embebida · acero sin grado confirmado; Estado del acabado: criterio_visual; Categoria: Cimentación industrial; ClaseIFC: IfcPlate; EstadoDeInformacion: provisional; UsoDeLasMagnitudes: Geometría de coordinación. Los volúmenes de referencia y subcomponentes no son cantidades de material ni componentes de fabricación certificados.
JH_EvidenciaDeMaterial - name: Acero de placa embebida · grado pendiente de confirmar; status: Dimensiones documentadas; grado sin confirmar; source: Detalles MJ-1/MJ-2/M1
JH_CapaBIM - IdentificadorCapa: foundations; NombreCapa: Cimentaciones; Funcion: Cimentación industrial; VisibilidadInicial: yes
JH_AcabadoVisual - Perfil: steel_embedded; Acabado: Placa embebida · acero sin grado confirmado; ColorRGB: [0.454902,0.486275,0.501961]; Rugosidad: 0.45; Metallicidad: 0.78; Estado: criterio_visual; Referencia: Interpretación visual del material documental; el acabado, tono y parámetros PBR no son una especificación contractual.; Nota: La apariencia no certifica el material físico ni el acabado de fabricación.
Name | Extensión de la malla en X (m) = ExtensionX (m) | Extensión de la malla en Y (m) = ExtensionY (m) | Extensión de la malla en Z (m) = ExtensionZ (m) = Espesor o altura real de sección (m) | Cota inferior de visualización (m) | Cota superior de visualización (m) | SuperficieDeLaMalla (m2) | VolumenGeometrico (m3) = Volumen geométrico (m³) | source = DocumentoFuente | dimensions | issues = IncidenciasPendientes | positioning = PosicionYEstado | assemblyId = Conjunto de cimentación | equipmentIds | supportPositionIds | sectionRef = Sección de referencia | sourceCadHandles | stableElementKey | geometryMetrics | visualizationIdentity | Identificadores CAD de referencia | Cota inferior relativa (m) = Cota inferior relativa adoptada (m) | Cota superior relativa (m) = Cota superior relativa adoptada (m) | Área de planta (m²) | Estado de la geometría | Identificador | Extensión local X (m) = Extensión local Y (m) | Espesor de placa (m) | Origen del espesor de placa | Código original en tabla | Carga vertical indicada | Posición E/N de la tabla (mm)
Cimentación de las cajas frías · placa embebida MJ-2 2423 | 0.450754 | 0.450753 | 0.016 | 286.184 | 286.2 | 0.3456 | 0.00256 | {"documentId":"LHD2609-JG00100-20260904","title":"Cimentaciones de equipos y pedestales del fabricante · revisión recibida 04/09/2026","date":"2026-09-04","sheet":"4–4 / 4a–4a","fileName":"LHD2609-JG00100_20260904.dwg","revisionCaveat":"Fecha de revisión tomada del nombre recibido; cajetines internos mantienen 02/07/2026 y algunos textos de plantilla.","sourceFileSha256":"b42eb027b7bc0b14c38d1d13514f4899b58a732aa8d0ba2ccf10fa2fc3192890"} | {"documented":[{"label":"Extensión local X","value":0.4,"unit":"m","source":"240F/2423, 1FCF3","status":"derivada del contorno CAD"},{"label":"Extensión local Y","value":0.4,"unit":"m","source":"240F/2423, 1FCF3","status":"derivada del contorno CAD"},{"label":"Cota inferior relativa adoptada","value":0.084,"unit":"m","source":"4–4 / 4a–4a","status":"interpretación con conflicto conservado"},{"label":"Cota superior relativa adoptada","value":0.1,"unit":"m","source":"4–4 / 4a–4a","status":"documentada / separación por material"}],"geometry":[{"label":"Extensión de la malla en X","value":0.45075400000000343,"unit":"m","source":"Geometría releída del IFC; datum absoluto de proceso provisional","status":"derivado"},{"label":"Extensión de la malla en Y","value":0.45075299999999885,"unit":"m","source":"Geometría releída del IFC; datum absoluto de proceso provisional","status":"derivado"},{"label":"Extensión de la malla en Z","value":0.016000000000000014,"unit":"m","source":"Geometría releída del IFC; datum absoluto de proceso provisional","status":"derivado"},{"label":"Cota inferior de visualización","value":286.184,"unit":"m","source":"Geometría releída del IFC; datum absoluto de proceso provisional","status":"derivado"},{"label":"Cota superior de visualización","value":286.2,"unit":"m","source":"Geometría releída del IFC; datum absoluto de proceso provisional","status":"derivado"}]} | ["Sección 4–4: etiqueta inferior −1,000 m frente a 1500 mm. Sección 4a–4a y espesor1500 mm: −1,500 m. Se adopta −1,500 m; conflicto pendiente."] | {"Cota inferior relativa (m)":0.084,"Cota superior relativa (m)":0.1,"Cero absoluto de visualización (m)":286.1,"Estado del cero absoluto":"Provisional","Criterio":"Las cotas relativas proceden del dibujo; la equivalencia absoluta no está confirmada."} | F-CB | ["CB-MAIN","CB-HX-PLAN","CB-EXP-N-PLAN","CB-EXP-W-PLAN"] | [] | 4–4 / 4a–4a | ["240F/2423","1FCF3"] | F-CB/Cimentación de las cajas frías · placa embebida MJ-2 2423 | {"boundingBoxM":{"min":[50.889249,47.745365,1.184],"max":[51.340003,48.196118,1.2]},"extentsM":[0.450754,0.450753,0.016],"meshSurfaceM2":0.3456,"meshVolumeM3":0.00256,"closedSolid":true,"basis":"Magnitudes de las mallas representadas, no cantidades certificadas de obra, compra o fabricación. Las partes pueden compartir superficies; no se suman como un despiece de materiales."} | {"elementId":"found_0904_323dc0fbe26a0b","ifcGuid":"3IW1afS4DGaBPsN1l43tI3","ifcClass":"IfcPlate","buildingId":"process_plant","buildingName":"Zona de separación de aire","sourceDocumentId":"LHD2609-JG00100-20260904","sourceRepresentationKind":"foundation"} | 240F/2423, 1FCF3 | 0.084 | 0.1 | 0.16 | Sección y contornos del fabricante; incidencias conservadas | found_0904_323dc0fbe26a0b | 0.4 | JH_InformacionBIM - conceptualReferenceIds: ["CB-HX-CONCEPT","CB-EXP-N-CONCEPT","CB-EXP-W-CONCEPT"]; JH_Trazabilidad - Equipos asociados: CB-MAIN, CB-HX-PLAN, CB-EXP-N-PLAN, CB-EXP-W-PLAN; Incidencias de origen: Sección 4–4: etiqueta inferior −1,000 m frente a 1500 mm. Sección 4a–4a y espesor1500 mm: −1,500 m. Se adopta −1,500 m; conflicto pendiente.; Detalle de placa: 400 × 400 × 16 mm; queda embebida en la plataforma superior.; JH_ReferenciasDeEsquema - ObjetosIlustrativos: ["CB-HX-CONCEPT","CB-EXP-N-CONCEPT","CB-EXP-W-CONCEPT"]; Nota: Relación de visualización, no conexión de montaje aprobada.
Cimentación de las cajas frías · placa embebida MJ-2 2424 | 0.450754 | 0.450754 | 0.016 | 286.184 | 286.2 | 0.3456 | 0.00256 | {"documentId":"LHD2609-JG00100-20260904","title":"Cimentaciones de equipos y pedestales del fabricante · revisión recibida 04/09/2026","date":"2026-09-04","sheet":"4–4 / 4a–4a","fileName":"LHD2609-JG00100_20260904.dwg","revisionCaveat":"Fecha de revisión tomada del nombre recibido; cajetines internos mantienen 02/07/2026 y algunos textos de plantilla.","sourceFileSha256":"b42eb027b7bc0b14c38d1d13514f4899b58a732aa8d0ba2ccf10fa2fc3192890"} | {"documented":[{"label":"Extensión local X","value":0.4,"unit":"m","source":"240F/2424, 1FCF3","status":"derivada del contorno CAD"},{"label":"Extensión local Y","value":0.4,"unit":"m","source":"240F/2424, 1FCF3","status":"derivada del contorno CAD"},{"label":"Cota inferior relativa adoptada","value":0.084,"unit":"m","source":"4–4 / 4a–4a","status":"interpretación con conflicto conservado"},{"label":"Cota superior relativa adoptada","value":0.1,"unit":"m","source":"4–4 / 4a–4a","status":"documentada / separación por material"}],"geometry":[{"label":"Extensión de la malla en X","value":0.4507539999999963,"unit":"m","source":"Geometría releída del IFC; datum absoluto de proceso provisional","status":"derivado"},{"label":"Extensión de la malla en Y","value":0.45075400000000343,"unit":"m","source":"Geometría releída del IFC; datum absoluto de proceso provisional","status":"derivado"},{"label":"Extensión de la malla en Z","value":0.016000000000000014,"unit":"m","source":"Geometría releída del IFC; datum absoluto de proceso provisional","status":"derivado"},{"label":"Cota inferior de visualización","value":286.184,"unit":"m","source":"Geometría releída del IFC; datum absoluto de proceso provisional","status":"derivado"},{"label":"Cota superior de visualización","value":286.2,"unit":"m","source":"Geometría releída del IFC; datum absoluto de proceso provisional","status":"derivado"}]} | ["Sección 4–4: etiqueta inferior −1,000 m frente a 1500 mm. Sección 4a–4a y espesor1500 mm: −1,500 m. Se adopta −1,500 m; conflicto pendiente."] | {"Cota inferior relativa (m)":0.084,"Cota superior relativa (m)":0.1,"Cero absoluto de visualización (m)":286.1,"Estado del cero absoluto":"Provisional","Criterio":"Las cotas relativas proceden del dibujo; la equivalencia absoluta no está confirmada."} | F-CB | ["CB-MAIN","CB-HX-PLAN","CB-EXP-N-PLAN","CB-EXP-W-PLAN"] | [] | 4–4 / 4a–4a | ["240F/2424","1FCF3"] | F-CB/Cimentación de las cajas frías · placa embebida MJ-2 2424 | {"boundingBoxM":{"min":[55.716425,49.817192,1.184],"max":[56.167179,50.267946,1.2]},"extentsM":[0.450754,0.450754,0.016],"meshSurfaceM2":0.3456,"meshVolumeM3":0.00256,"closedSolid":true,"basis":"Magnitudes de las mallas representadas, no cantidades certificadas de obra, compra o fabricación. Las partes pueden compartir superficies; no se suman como un despiece de materiales."} | {"elementId":"found_0904_3aab66a70a9bd0","ifcGuid":"2zX7Ks4OfPUvhD$KTgNGrU","ifcClass":"IfcPlate","buildingId":"process_plant","buildingName":"Zona de separación de aire","sourceDocumentId":"LHD2609-JG00100-20260904","sourceRepresentationKind":"foundation"} | 240F/2424, 1FCF3 | 0.084 | 0.1 | 0.16 | Sección y contornos del fabricante; incidencias conservadas | found_0904_3aab66a70a9bd0 | 0.4 | JH_InformacionBIM - conceptualReferenceIds: ["CB-HX-CONCEPT","CB-EXP-N-CONCEPT","CB-EXP-W-CONCEPT"]; JH_Trazabilidad - Equipos asociados: CB-MAIN, CB-HX-PLAN, CB-EXP-N-PLAN, CB-EXP-W-PLAN; Incidencias de origen: Sección 4–4: etiqueta inferior −1,000 m frente a 1500 mm. Sección 4a–4a y espesor1500 mm: −1,500 m. Se adopta −1,500 m; conflicto pendiente.; Detalle de placa: 400 × 400 × 16 mm; queda embebida en la plataforma superior.; JH_ReferenciasDeEsquema - ObjetosIlustrativos: ["CB-HX-CONCEPT","CB-EXP-N-CONCEPT","CB-EXP-W-CONCEPT"]; Nota: Relación de visualización, no conexión de montaje aprobada.
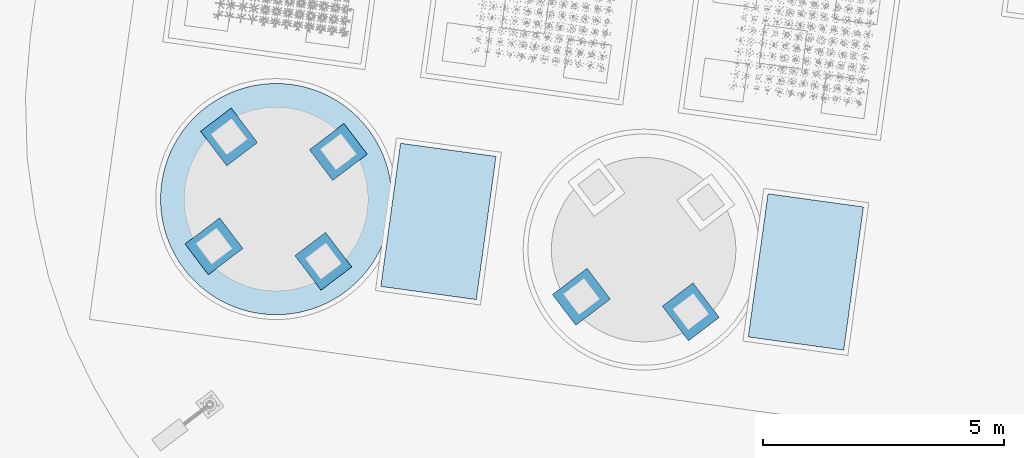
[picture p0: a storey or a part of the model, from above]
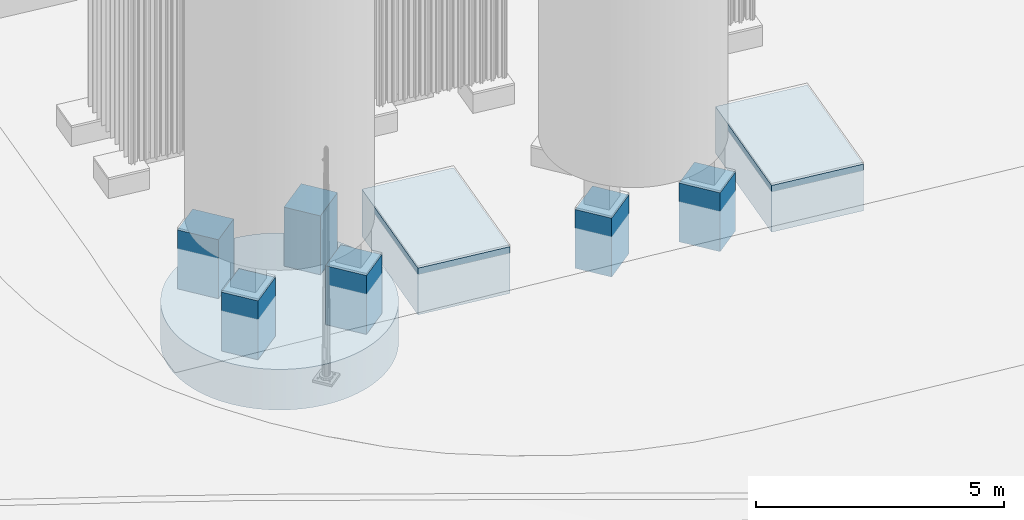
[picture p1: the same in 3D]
Properties of the parts of a building model (IFC4), part 98 of 134

# IfcPlate: Cimentación industrial (48)
Name | Extensión de la malla en X (m) = ExtensionX (m) | Extensión de la malla en Y (m) = ExtensionY (m) | Extensión de la malla en Z (m) = ExtensionZ (m) = Espesor o altura real de sección (m) | Cota inferior de visualización (m) | Cota superior de visualización (m) | SuperficieDeLaMalla (m2) | VolumenGeometrico (m3) = Volumen geométrico (m³) | source = DocumentoFuente | dimensions | issues = IncidenciasPendientes | positioning = PosicionYEstado | assemblyId = Conjunto de cimentación | equipmentIds | supportPositionIds | sectionRef = Sección de referencia | sourceCadHandles | stableElementKey | geometryMetrics | visualizationIdentity | Identificadores CAD de referencia | Cota inferior relativa (m) = Cota inferior relativa adoptada (m) | Cota superior relativa (m) = Cota superior relativa adoptada (m) | Área de planta (m²) | Estado de la geometría | Identificador | Extensión local X (m) = Extensión local Y (m) | Espesor de placa (m) | Origen del espesor de placa | Código original en tabla | Carga vertical indicada | Posición E/N de la tabla (mm)
Cimentación de las cajas frías · placa embebida MJ-2 2427 | 0.450754 | 0.450753 | 0.016 | 286.184 | 286.2 | 0.3456 | 0.00256 | {"documentId":"LHD2609-JG00100-20260904","title":"Cimentaciones de equipos y pedestales del fabricante · revisión recibida 04/09/2026","date":"2026-09-04","sheet":"4–4 / 4a–4a","fileName":"LHD2609-JG00100_20260904.dwg","revisionCaveat":"Fecha de revisión tomada del nombre recibido; cajetines internos mantienen 02/07/2026 y algunos textos de plantilla.","sourceFileSha256":"b42eb027b7bc0b14c38d1d13514f4899b58a732aa8d0ba2ccf10fa2fc3192890"} | {"documented":[{"label":"Extensión local X","value":0.4,"unit":"m","source":"240F/2427, 1FCF3","status":"derivada del contorno CAD"},{"label":"Extensión local Y","value":0.4,"unit":"m","source":"240F/2427, 1FCF3","status":"derivada del contorno CAD"},{"label":"Cota inferior relativa adoptada","value":0.084,"unit":"m","source":"4–4 / 4a–4a","status":"interpretación con conflicto conservado"},{"label":"Cota superior relativa adoptada","value":0.1,"unit":"m","source":"4–4 / 4a–4a","status":"documentada / separación por material"}],"geometry":[{"label":"Extensión de la malla en X","value":0.4507539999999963,"unit":"m","source":"Geometría releída del IFC; datum absoluto de proceso provisional","status":"derivado"},{"label":"Extensión de la malla en Y","value":0.45075299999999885,"unit":"m","source":"Geometría releída del IFC; datum absoluto de proceso provisional","status":"derivado"},{"label":"Extensión de la malla en Z","value":0.016000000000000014,"unit":"m","source":"Geometría releída del IFC; datum absoluto de proceso provisional","status":"derivado"},{"label":"Cota inferior de visualización","value":286.184,"unit":"m","source":"Geometría releída del IFC; datum absoluto de proceso provisional","status":"derivado"},{"label":"Cota superior de visualización","value":286.2,"unit":"m","source":"Geometría releída del IFC; datum absoluto de proceso provisional","status":"derivado"}]} | ["Sección 4–4: etiqueta inferior −1,000 m frente a 1500 mm. Sección 4a–4a y espesor1500 mm: −1,500 m. Se adopta −1,500 m; conflicto pendiente."] | {"Cota inferior relativa (m)":0.084,"Cota superior relativa (m)":0.1,"Cero absoluto de visualización (m)":286.1,"Estado del cero absoluto":"Provisional","Criterio":"Las cotas relativas proceden del dibujo; la equivalencia absoluta no está confirmada."} | F-CB | ["CB-MAIN","CB-HX-PLAN","CB-EXP-N-PLAN","CB-EXP-W-PLAN"] | [] | 4–4 / 4a–4a | ["240F/2427","1FCF3"] | F-CB/Cimentación de las cajas frías · placa embebida MJ-2 2427 | {"boundingBoxM":{"min":[57.598719,49.558405,1.184],"max":[58.049473,50.009158,1.2]},"extentsM":[0.450754,0.450753,0.016],"meshSurfaceM2":0.3456,"meshVolumeM3":0.00256,"closedSolid":true,"basis":"Magnitudes de las mallas representadas, no cantidades certificadas de obra, compra o fabricación. Las partes pueden compartir superficies; no se suman como un despiece de materiales."} | {"elementId":"found_0904_33c531229e93fa","ifcGuid":"3knnljj$1VxQH3$pTDMSUY","ifcClass":"IfcPlate","buildingId":"process_plant","buildingName":"Zona de separación de aire","sourceDocumentId":"LHD2609-JG00100-20260904","sourceRepresentationKind":"foundation"} | 240F/2427, 1FCF3 | 0.084 | 0.1 | 0.16 | Sección y contornos del fabricante; incidencias conservadas | found_0904_33c531229e93fa | 0.4 | JH_InformacionBIM - conceptualReferenceIds: ["CB-HX-CONCEPT","CB-EXP-N-CONCEPT","CB-EXP-W-CONCEPT"]; JH_Trazabilidad - Equipos asociados: CB-MAIN, CB-HX-PLAN, CB-EXP-N-PLAN, CB-EXP-W-PLAN; Incidencias de origen: Sección 4–4: etiqueta inferior −1,000 m frente a 1500 mm. Sección 4a–4a y espesor1500 mm: −1,500 m. Se adopta −1,500 m; conflicto pendiente.; Detalle de placa: 400 × 400 × 16 mm; queda embebida en la plataforma superior.; JH_ReferenciasDeEsquema - ObjetosIlustrativos: ["CB-HX-CONCEPT","CB-EXP-N-CONCEPT","CB-EXP-W-CONCEPT"]; Nota: Relación de visualización, no conexión de montaje aprobada.
Base de la caseta de analizadores · placa embebida MJ3 26DA | 0.225377 | 0.225377 | 0.014 | 286.286 | 286.3 | 0.0912 | 0.00056 | {"documentId":"LHD2609-JG00100-20260904","title":"Cimentaciones de equipos y pedestales del fabricante · revisión recibida 04/09/2026","date":"2026-09-04","sheet":"20–20","fileName":"LHD2609-JG00100_20260904.dwg","revisionCaveat":"Fecha de revisión tomada del nombre recibido; cajetines internos mantienen 02/07/2026 y algunos textos de plantilla.","sourceFileSha256":"b42eb027b7bc0b14c38d1d13514f4899b58a732aa8d0ba2ccf10fa2fc3192890"} | {"documented":[{"label":"Extensión local X","value":0.2,"unit":"m","source":"26CA/26DA, 24873","status":"derivada del contorno CAD"},{"label":"Extensión local Y","value":0.2,"unit":"m","source":"26CA/26DA, 24873","status":"derivada del contorno CAD"},{"label":"Cota inferior relativa adoptada","value":0.186,"unit":"m","source":"20–20","status":"documentada"},{"label":"Cota superior relativa adoptada","value":0.2,"unit":"m","source":"20–20","status":"documentada / separación por material"}],"geometry":[{"label":"Extensión de la malla en X","value":0.2253769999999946,"unit":"m","source":"Geometría releída del IFC; datum absoluto de proceso provisional","status":"derivado"},{"label":"Extensión de la malla en Y","value":0.22537700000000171,"unit":"m","source":"Geometría releída del IFC; datum absoluto de proceso provisional","status":"derivado"},{"label":"Extensión de la malla en Z","value":0.014000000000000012,"unit":"m","source":"Geometría releída del IFC; datum absoluto de proceso provisional","status":"derivado"},{"label":"Cota inferior de visualización","value":286.286,"unit":"m","source":"Geometría releída del IFC; datum absoluto de proceso provisional","status":"derivado"},{"label":"Cota superior de visualización","value":286.3,"unit":"m","source":"Geometría releída del IFC; datum absoluto de proceso provisional","status":"derivado"}]} | [] | {"Cota inferior relativa (m)":0.186,"Cota superior relativa (m)":0.2,"Cero absoluto de visualización (m)":286.1,"Estado del cero absoluto":"Provisional","Criterio":"Las cotas relativas proceden del dibujo; la equivalencia absoluta no está confirmada."} | F-ANALYSIS | ["ANALYSIS-CABIN"] | [] | 20–20 | ["26CA/26DA","24873"] | F-ANALYSIS/Base de la caseta de analizadores · placa embebida MJ3 26DA | {"boundingBoxM":{"min":[44.399489,41.831165,1.286],"max":[44.624866,42.056542,1.3]},"extentsM":[0.225377,0.225377,0.014],"meshSurfaceM2":0.0912,"meshVolumeM3":0.00056,"closedSolid":true,"basis":"Magnitudes de las mallas representadas, no cantidades certificadas de obra, compra o fabricación. Las partes pueden compartir superficies; no se suman como un despiece de materiales."} | {"elementId":"found_0904_5fe3eabcbe4201","ifcGuid":"1655xTvPrKXvgnTeFbLLFq","ifcClass":"IfcPlate","buildingId":"process_plant","buildingName":"Zona de separación de aire","sourceDocumentId":"LHD2609-JG00100-20260904","sourceRepresentationKind":"foundation"} | 26CA/26DA, 24873 | 0.186 | 0.2 | 0.04 | Contornos y sección documentados por el fabricante | found_0904_5fe3eabcbe4201 | 0.2 | JH_Trazabilidad - Equipos asociados: ANALYSIS-CABIN
Base de la caseta de analizadores · placa embebida MJ3 26DB | 0.225377 | 0.225377 | 0.014 | 286.286 | 286.3 | 0.0912 | 0.00056 | {"documentId":"LHD2609-JG00100-20260904","title":"Cimentaciones de equipos y pedestales del fabricante · revisión recibida 04/09/2026","date":"2026-09-04","sheet":"20–20","fileName":"LHD2609-JG00100_20260904.dwg","revisionCaveat":"Fecha de revisión tomada del nombre recibido; cajetines internos mantienen 02/07/2026 y algunos textos de plantilla.","sourceFileSha256":"b42eb027b7bc0b14c38d1d13514f4899b58a732aa8d0ba2ccf10fa2fc3192890"} | {"documented":[{"label":"Extensión local X","value":0.2,"unit":"m","source":"26CA/26DB, 24873","status":"derivada del contorno CAD"},{"label":"Extensión local Y","value":0.2,"unit":"m","source":"26CA/26DB, 24873","status":"derivada del contorno CAD"},{"label":"Cota inferior relativa adoptada","value":0.186,"unit":"m","source":"20–20","status":"documentada"},{"label":"Cota superior relativa adoptada","value":0.2,"unit":"m","source":"20–20","status":"documentada / separación por material"}],"geometry":[{"label":"Extensión de la malla en X","value":0.22537700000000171,"unit":"m","source":"Geometría releída del IFC; datum absoluto de proceso provisional","status":"derivado"},{"label":"Extensión de la malla en Y","value":0.22537700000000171,"unit":"m","source":"Geometría releída del IFC; datum absoluto de proceso provisional","status":"derivado"},{"label":"Extensión de la malla en Z","value":0.014000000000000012,"unit":"m","source":"Geometría releída del IFC; datum absoluto de proceso provisional","status":"derivado"},{"label":"Cota inferior de visualización","value":286.286,"unit":"m","source":"Geometría releída del IFC; datum absoluto de proceso provisional","status":"derivado"},{"label":"Cota superior de visualización","value":286.3,"unit":"m","source":"Geometría releída del IFC; datum absoluto de proceso provisional","status":"derivado"}]} | [] | {"Cota inferior relativa (m)":0.186,"Cota superior relativa (m)":0.2,"Cero absoluto de visualización (m)":286.1,"Estado del cero absoluto":"Provisional","Criterio":"Las cotas relativas proceden del dibujo; la equivalencia absoluta no está confirmada."} | F-ANALYSIS | ["ANALYSIS-CABIN"] | [] | 20–20 | ["26CA/26DB","24873"] | F-ANALYSIS/Base de la caseta de analizadores · placa embebida MJ3 26DB | {"boundingBoxM":{"min":[44.08622,39.552599,1.286],"max":[44.311597,39.777976,1.3]},"extentsM":[0.225377,0.225377,0.014],"meshSurfaceM2":0.0912,"meshVolumeM3":0.00056,"closedSolid":true,"basis":"Magnitudes de las mallas representadas, no cantidades certificadas de obra, compra o fabricación. Las partes pueden compartir superficies; no se suman como un despiece de materiales."} | {"elementId":"found_0904_c330c932b1c30a","ifcGuid":"3gLRmRWt9V3PKR5s9v$7h3","ifcClass":"IfcPlate","buildingId":"process_plant","buildingName":"Zona de separación de aire","sourceDocumentId":"LHD2609-JG00100-20260904","sourceRepresentationKind":"foundation"} | 26CA/26DB, 24873 | 0.186 | 0.2 | 0.04 | Contornos y sección documentados por el fabricante | found_0904_c330c932b1c30a | 0.2 | JH_Trazabilidad - Equipos asociados: ANALYSIS-CABIN
Base de la caseta de analizadores · placa embebida MJ3 26DC | 0.225377 | 0.225377 | 0.014 | 286.286 | 286.3 | 0.0912 | 0.00056 | {"documentId":"LHD2609-JG00100-20260904","title":"Cimentaciones de equipos y pedestales del fabricante · revisión recibida 04/09/2026","date":"2026-09-04","sheet":"20–20","fileName":"LHD2609-JG00100_20260904.dwg","revisionCaveat":"Fecha de revisión tomada del nombre recibido; cajetines internos mantienen 02/07/2026 y algunos textos de plantilla.","sourceFileSha256":"b42eb027b7bc0b14c38d1d13514f4899b58a732aa8d0ba2ccf10fa2fc3192890"} | {"documented":[{"label":"Extensión local X","value":0.2,"unit":"m","source":"26CA/26DC, 24873","status":"derivada del contorno CAD"},{"label":"Extensión local Y","value":0.2,"unit":"m","source":"26CA/26DC, 24873","status":"derivada del contorno CAD"},{"label":"Cota inferior relativa adoptada","value":0.186,"unit":"m","source":"20–20","status":"documentada"},{"label":"Cota superior relativa adoptada","value":0.2,"unit":"m","source":"20–20","status":"documentada / separación por material"}],"geometry":[{"label":"Extensión de la malla en X","value":0.22537700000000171,"unit":"m","source":"Geometría releída del IFC; datum absoluto de proceso provisional","status":"derivado"},{"label":"Extensión de la malla en Y","value":0.22537700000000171,"unit":"m","source":"Geometría releída del IFC; datum absoluto de proceso provisional","status":"derivado"},{"label":"Extensión de la malla en Z","value":0.014000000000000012,"unit":"m","source":"Geometría releída del IFC; datum absoluto de proceso provisional","status":"derivado"},{"label":"Cota inferior de visualización","value":286.286,"unit":"m","source":"Geometría releída del IFC; datum absoluto de proceso provisional","status":"derivado"},{"label":"Cota superior de visualización","value":286.3,"unit":"m","source":"Geometría releída del IFC; datum absoluto de proceso provisional","status":"derivado"}]} | [] | {"Cota inferior relativa (m)":0.186,"Cota superior relativa (m)":0.2,"Cero absoluto de visualización (m)":286.1,"Estado del cero absoluto":"Provisional","Criterio":"Las cotas relativas proceden del dibujo; la equivalencia absoluta no está confirmada."} | F-ANALYSIS | ["ANALYSIS-CABIN"] | [] | 20–20 | ["26CA/26DC","24873"] | F-ANALYSIS/Base de la caseta de analizadores · placa embebida MJ3 26DC | {"boundingBoxM":{"min":[46.826657,41.497465,1.286],"max":[47.052034,41.722842,1.3]},"extentsM":[0.225377,0.225377,0.014],"meshSurfaceM2":0.0912,"meshVolumeM3":0.00056,"closedSolid":true,"basis":"Magnitudes de las mallas representadas, no cantidades certificadas de obra, compra o fabricación. Las partes pueden compartir superficies; no se suman como un despiece de materiales."} | {"elementId":"found_0904_a18f40c00197ec","ifcGuid":"3_sBKwWhvU3ggJN51k8myG","ifcClass":"IfcPlate","buildingId":"process_plant","buildingName":"Zona de separación de aire","sourceDocumentId":"LHD2609-JG00100-20260904","sourceRepresentationKind":"foundation"} | 26CA/26DC, 24873 | 0.186 | 0.2 | 0.04 | Contornos y sección documentados por el fabricante | found_0904_a18f40c00197ec | 0.2 | JH_Trazabilidad - Equipos asociados: ANALYSIS-CABIN
Base de la caseta de analizadores · placa embebida MJ3 26DD | 0.225377 | 0.225377 | 0.014 | 286.286 | 286.3 | 0.0912 | 0.00056 | {"documentId":"LHD2609-JG00100-20260904","title":"Cimentaciones de equipos y pedestales del fabricante · revisión recibida 04/09/2026","date":"2026-09-04","sheet":"20–20","fileName":"LHD2609-JG00100_20260904.dwg","revisionCaveat":"Fecha de revisión tomada del nombre recibido; cajetines internos mantienen 02/07/2026 y algunos textos de plantilla.","sourceFileSha256":"b42eb027b7bc0b14c38d1d13514f4899b58a732aa8d0ba2ccf10fa2fc3192890"} | {"documented":[{"label":"Extensión local X","value":0.2,"unit":"m","source":"26CA/26DD, 24873","status":"derivada del contorno CAD"},{"label":"Extensión local Y","value":0.2,"unit":"m","source":"26CA/26DD, 24873","status":"derivada del contorno CAD"},{"label":"Cota inferior relativa adoptada","value":0.186,"unit":"m","source":"20–20","status":"documentada"},{"label":"Cota superior relativa adoptada","value":0.2,"unit":"m","source":"20–20","status":"documentada / separación por material"}],"geometry":[{"label":"Extensión de la malla en X","value":0.22537700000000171,"unit":"m","source":"Geometría releída del IFC; datum absoluto de proceso provisional","status":"derivado"},{"label":"Extensión de la malla en Y","value":0.22537700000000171,"unit":"m","source":"Geometría releída del IFC; datum absoluto de proceso provisional","status":"derivado"},{"label":"Extensión de la malla en Z","value":0.014000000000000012,"unit":"m","source":"Geometría releída del IFC; datum absoluto de proceso provisional","status":"derivado"},{"label":"Cota inferior de visualización","value":286.286,"unit":"m","source":"Geometría releída del IFC; datum absoluto de proceso provisional","status":"derivado"},{"label":"Cota superior de visualización","value":286.3,"unit":"m","source":"Geometría releída del IFC; datum absoluto de proceso provisional","status":"derivado"}]} | [] | {"Cota inferior relativa (m)":0.186,"Cota superior relativa (m)":0.2,"Cero absoluto de visualización (m)":286.1,"Estado del cero absoluto":"Provisional","Criterio":"Las cotas relativas proceden del dibujo; la equivalencia absoluta no está confirmada."} | F-ANALYSIS | ["ANALYSIS-CABIN"] | [] | 20–20 | ["26CA/26DD","24873"] | F-ANALYSIS/Base de la caseta de analizadores · placa embebida MJ3 26DD | {"boundingBoxM":{"min":[46.513388,39.218899,1.286],"max":[46.738765,39.444276,1.3]},"extentsM":[0.225377,0.225377,0.014],"meshSurfaceM2":0.0912,"meshVolumeM3":0.00056,"closedSolid":true,"basis":"Magnitudes de las mallas representadas, no cantidades certificadas de obra, compra o fabricación. Las partes pueden compartir superficies; no se suman como un despiece de materiales."} | {"elementId":"found_0904_181c1ed7abf435","ifcGuid":"2E$tEMkH9Q9AGVikY9yEzQ","ifcClass":"IfcPlate","buildingId":"process_plant","buildingName":"Zona de separación de aire","sourceDocumentId":"LHD2609-JG00100-20260904","sourceRepresentationKind":"foundation"} | 26CA/26DD, 24873 | 0.186 | 0.2 | 0.04 | Contornos y sección documentados por el fabricante | found_0904_181c1ed7abf435 | 0.2 | JH_Trazabilidad - Equipos asociados: ANALYSIS-CABIN
Cimentación de soporte de tuberías C01 · placa embebida MJ-1 | 0.450754 | 0.450754 | 0.02 | 286.28 | 286.3 | 0.352 | 0.0032 | {"documentId":"LHD2609-JG00100-20260904","title":"Cimentaciones de equipos y pedestales del fabricante · revisión recibida 04/09/2026","date":"2026-09-04","sheet":"ZD1 / DZ-1","fileName":"LHD2609-JG00100_20260904.dwg","revisionCaveat":"Fecha de revisión tomada del nombre recibido; cajetines internos mantienen 02/07/2026 y algunos textos de plantilla.","sourceFileSha256":"b42eb027b7bc0b14c38d1d13514f4899b58a732aa8d0ba2ccf10fa2fc3192890"} | {"documented":[{"label":"Extensión local X","value":0.4,"unit":"m","source":"2CC56, 2CC2F, 2CCC9, 2CC64, 2CC21, 2CC28, 2CCA9, 2CEA7, 2CE82","status":"derivada del contorno CAD"},{"label":"Extensión local Y","value":0.4,"unit":"m","source":"2CC56, 2CC2F, 2CCC9, 2CC64, 2CC21, 2CC28, 2CCA9, 2CEA7, 2CE82","status":"derivada del contorno CAD"},{"label":"Cota inferior relativa adoptada","value":0.18000000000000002,"unit":"m","source":"ZD1 / DZ-1","status":"documentada"},{"label":"Cota superior relativa adoptada","value":0.2,"unit":"m","source":"ZD1 / DZ-1","status":"documentada / separación por material"}],"geometry":[{"label":"Extensión de la malla en X","value":0.4507539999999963,"unit":"m","source":"Geometría releída del IFC; datum absoluto de proceso provisional","status":"derivado"},{"label":"Extensión de la malla en Y","value":0.45075400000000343,"unit":"m","source":"Geometría releída del IFC; datum absoluto de proceso provisional","status":"derivado"},{"label":"Extensión de la malla en Z","value":0.020000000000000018,"unit":"m","source":"Geometría releída del IFC; datum absoluto de proceso provisional","status":"derivado"},{"label":"Cota inferior de visualización","value":286.28,"unit":"m","source":"Geometría releída del IFC; datum absoluto de proceso provisional","status":"derivado"},{"label":"Cota superior de visualización","value":286.3,"unit":"m","source":"Geometría releída del IFC; datum absoluto de proceso provisional","status":"derivado"}]} | [] | {"Cota inferior relativa (m)":0.18000000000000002,"Cota superior relativa (m)":0.2,"Cero absoluto de visualización (m)":286.1,"Estado del cero absoluto":"Provisional","Criterio":"Las cotas relativas proceden del dibujo; la equivalencia absoluta no está confirmada."} | SUP-C01 | [] | ["C01"] | ZD1 / DZ-1 | ["2CC56","2CC2F","2CCC9","2CC64","2CC21","2CC28","2CCA9","2CEA7","2CE82"] | SUP-C01/Cimentación de soporte de tuberías C01 · placa embebida MJ-1 | {"boundingBoxM":{"min":[48.14495,79.141735,1.28],"max":[48.595704,79.592489,1.3]},"extentsM":[0.450754,0.450754,0.02],"meshSurfaceM2":0.352,"meshVolumeM3":0.0032,"closedSolid":true,"basis":"Magnitudes de las mallas representadas, no cantidades certificadas de obra, compra o fabricación. Las partes pueden compartir superficies; no se suman como un despiece de materiales."} | {"elementId":"found_0904_d0d6683a6d03e8","ifcGuid":"2wTIGPqjLJZQ$7oSbRyBDC","ifcClass":"IfcPlate","buildingId":"process_plant","buildingName":"Zona de separación de aire","sourceDocumentId":"LHD2609-JG00100-20260904","sourceRepresentationKind":"foundation"} | 2CC56, 2CC2F, 2CCC9, 2CC64, 2CC21, 2CC28, 2CCA9, 2CEA7, 2CE82 | 0.18 | 0.2 | 0.16 | Contornos y sección documentados por el fabricante | found_0904_d0d6683a6d03e8 | 0.4 | 0.02 | M1: detalle20 mm; MJ1/MJ2:20 mm derivados del contorno lateral80 mm a escala4, no de una cota explícita. | C01 | Fz=-2000 | 9000.0 / 51050.0
Cimentación de soporte de tuberías C02 · placa embebida MJ-1 | 0.450754 | 0.450754 | 0.02 | 286.28 | 286.3 | 0.352 | 0.0032 | {"documentId":"LHD2609-JG00100-20260904","title":"Cimentaciones de equipos y pedestales del fabricante · revisión recibida 04/09/2026","date":"2026-09-04","sheet":"ZD1 / DZ-1","fileName":"LHD2609-JG00100_20260904.dwg","revisionCaveat":"Fecha de revisión tomada del nombre recibido; cajetines internos mantienen 02/07/2026 y algunos textos de plantilla.","sourceFileSha256":"b42eb027b7bc0b14c38d1d13514f4899b58a732aa8d0ba2ccf10fa2fc3192890"} | {"documented":[{"label":"Extensión local X","value":0.4,"unit":"m","source":"2CC57, 2CD32, 2CD35, 2CD33, 2CD30, 2CD31, 2CD34, 2CEA8, 2CE83","status":"derivada del contorno CAD"},{"label":"Extensión local Y","value":0.4,"unit":"m","source":"2CC57, 2CD32, 2CD35, 2CD33, 2CD30, 2CD31, 2CD34, 2CEA8, 2CE83","status":"derivada del contorno CAD"},{"label":"Cota inferior relativa adoptada","value":0.18000000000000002,"unit":"m","source":"ZD1 / DZ-1","status":"documentada"},{"label":"Cota superior relativa adoptada","value":0.2,"unit":"m","source":"ZD1 / DZ-1","status":"documentada / separación por material"}],"geometry":[{"label":"Extensión de la malla en X","value":0.4507539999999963,"unit":"m","source":"Geometría releída del IFC; datum absoluto de proceso provisional","status":"derivado"},{"label":"Extensión de la malla en Y","value":0.4507539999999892,"unit":"m","source":"Geometría releída del IFC; datum absoluto de proceso provisional","status":"derivado"},{"label":"Extensión de la malla en Z","value":0.020000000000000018,"unit":"m","source":"Geometría releída del IFC; datum absoluto de proceso provisional","status":"derivado"},{"label":"Cota inferior de visualización","value":286.28,"unit":"m","source":"Geometría releída del IFC; datum absoluto de proceso provisional","status":"derivado"},{"label":"Cota superior de visualización","value":286.3,"unit":"m","source":"Geometría releída del IFC; datum absoluto de proceso provisional","status":"derivado"}]} | [] | {"Cota inferior relativa (m)":0.18000000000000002,"Cota superior relativa (m)":0.2,"Cero absoluto de visualización (m)":286.1,"Estado del cero absoluto":"Provisional","Criterio":"Las cotas relativas proceden del dibujo; la equivalencia absoluta no está confirmada."} | SUP-C02 | [] | ["C02"] | ZD1 / DZ-1 | ["2CC57","2CD32","2CD35","2CD33","2CD30","2CD31","2CD34","2CEA8","2CE83"] | SUP-C02/Cimentación de soporte de tuberías C02 · placa embebida MJ-1 | {"boundingBoxM":{"min":[48.005341,78.126287,1.28],"max":[48.456095,78.577041,1.3]},"extentsM":[0.450754,0.450754,0.02],"meshSurfaceM2":0.352,"meshVolumeM3":0.0032,"closedSolid":true,"basis":"Magnitudes de las mallas representadas, no cantidades certificadas de obra, compra o fabricación. Las partes pueden compartir superficies; no se suman como un despiece de materiales."} | {"elementId":"found_0904_97d844311f5630","ifcGuid":"3ABruXmHXIlBMbH9v_RhoF","ifcClass":"IfcPlate","buildingId":"process_plant","buildingName":"Zona de separación de aire","sourceDocumentId":"LHD2609-JG00100-20260904","sourceRepresentationKind":"foundation"} | 2CC57, 2CD32, 2CD35, 2CD33, 2CD30, 2CD31, 2CD34, 2CEA8, 2CE83 | 0.18 | 0.2 | 0.16 | Contornos y sección documentados por el fabricante | found_0904_97d844311f5630 | 0.4 | 0.02 | M1: detalle20 mm; MJ1/MJ2:20 mm derivados del contorno lateral80 mm a escala4, no de una cota explícita. | C02 | Fz=-2000 | 9000.0 / 50025.0
Cimentación de soporte de tuberías C03 · placa embebida MJ-1 | 0.450754 | 0.450754 | 0.02 | 286.28 | 286.3 | 0.352 | 0.0032 | {"documentId":"LHD2609-JG00100-20260904","title":"Cimentaciones de equipos y pedestales del fabricante · revisión recibida 04/09/2026","date":"2026-09-04","sheet":"ZD1 / DZ-1","fileName":"LHD2609-JG00100_20260904.dwg","revisionCaveat":"Fecha de revisión tomada del nombre recibido; cajetines internos mantienen 02/07/2026 y algunos textos de plantilla.","sourceFileSha256":"b42eb027b7bc0b14c38d1d13514f4899b58a732aa8d0ba2ccf10fa2fc3192890"} | {"documented":[{"label":"Extensión local X","value":0.4,"unit":"m","source":"2CC58, 2CD38, 2CD3B, 2CD39, 2CD36, 2CD37, 2CD3A, 2CEA9, 2CE84","status":"derivada del contorno CAD"},{"label":"Extensión local Y","value":0.4,"unit":"m","source":"2CC58, 2CD38, 2CD3B, 2CD39, 2CD36, 2CD37, 2CD3A, 2CEA9, 2CE84","status":"derivada del contorno CAD"},{"label":"Cota inferior relativa adoptada","value":0.18000000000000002,"unit":"m","source":"ZD1 / DZ-1","status":"documentada"},{"label":"Cota superior relativa adoptada","value":0.2,"unit":"m","source":"ZD1 / DZ-1","status":"documentada / separación por material"}],"geometry":[{"label":"Extensión de la malla en X","value":0.45075400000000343,"unit":"m","source":"Geometría releída del IFC; datum absoluto de proceso provisional","status":"derivado"},{"label":"Extensión de la malla en Y","value":0.45075400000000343,"unit":"m","source":"Geometría releída del IFC; datum absoluto de proceso provisional","status":"derivado"},{"label":"Extensión de la malla en Z","value":0.020000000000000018,"unit":"m","source":"Geometría releída del IFC; datum absoluto de proceso provisional","status":"derivado"},{"label":"Cota inferior de visualización","value":286.28,"unit":"m","source":"Geometría releída del IFC; datum absoluto de proceso provisional","status":"derivado"},{"label":"Cota superior de visualización","value":286.3,"unit":"m","source":"Geometría releída del IFC; datum absoluto de proceso provisional","status":"derivado"}]} | [] | {"Cota inferior relativa (m)":0.18000000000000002,"Cota superior relativa (m)":0.2,"Cero absoluto de visualización (m)":286.1,"Estado del cero absoluto":"Provisional","Criterio":"Las cotas relativas proceden del dibujo; la equivalencia absoluta no está confirmada."} | SUP-C03 | [] | ["C03"] | ZD1 / DZ-1 | ["2CC58","2CD38","2CD3B","2CD39","2CD36","2CD37","2CD3A","2CEA9","2CE84"] | SUP-C03/Cimentación de soporte de tuberías C03 · placa embebida MJ-1 | {"boundingBoxM":{"min":[54.237637,78.304081,1.28],"max":[54.688391,78.754835,1.3]},"extentsM":[0.450754,0.450754,0.02],"meshSurfaceM2":0.352,"meshVolumeM3":0.0032,"closedSolid":true,"basis":"Magnitudes de las mallas representadas, no cantidades certificadas de obra, compra o fabricación. Las partes pueden compartir superficies; no se suman como un despiece de materiales."} | {"elementId":"found_0904_4baf35b15a6022","ifcGuid":"3LEPPCo25H6QtdwQIK043B","ifcClass":"IfcPlate","buildingId":"process_plant","buildingName":"Zona de separación de aire","sourceDocumentId":"LHD2609-JG00100-20260904","sourceRepresentationKind":"foundation"} | 2CC58, 2CD38, 2CD3B, 2CD39, 2CD36, 2CD37, 2CD3A, 2CEA9, 2CE84 | 0.18 | 0.2 | 0.16 | Contornos y sección documentados por el fabricante | found_0904_4baf35b15a6022 | 0.4 | 0.02 | M1: detalle20 mm; MJ1/MJ2:20 mm derivados del contorno lateral80 mm a escala4, no de una cota explícita. | C03 | Fz=-2000 | 15150.0 / 51050.0
Cimentación de soporte de tuberías C04 · placa embebida MJ-1 | 0.450754 | 0.450754 | 0.02 | 286.28 | 286.3 | 0.352 | 0.0032 | {"documentId":"LHD2609-JG00100-20260904","title":"Cimentaciones de equipos y pedestales del fabricante · revisión recibida 04/09/2026","date":"2026-09-04","sheet":"ZD1 / DZ-1","fileName":"LHD2609-JG00100_20260904.dwg","revisionCaveat":"Fecha de revisión tomada del nombre recibido; cajetines internos mantienen 02/07/2026 y algunos textos de plantilla.","sourceFileSha256":"b42eb027b7bc0b14c38d1d13514f4899b58a732aa8d0ba2ccf10fa2fc3192890"} | {"documented":[{"label":"Extensión local X","value":0.4,"unit":"m","source":"2CC59, 2CD3E, 2CD41, 2CD3F, 2CD3C, 2CD3D, 2CD40, 2CEAA, 2CE85","status":"derivada del contorno CAD"},{"label":"Extensión local Y","value":0.4,"unit":"m","source":"2CC59, 2CD3E, 2CD41, 2CD3F, 2CD3C, 2CD3D, 2CD40, 2CEAA, 2CE85","status":"derivada del contorno CAD"},{"label":"Cota inferior relativa adoptada","value":0.18000000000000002,"unit":"m","source":"ZD1 / DZ-1","status":"documentada"},{"label":"Cota superior relativa adoptada","value":0.2,"unit":"m","source":"ZD1 / DZ-1","status":"documentada / separación por material"}],"geometry":[{"label":"Extensión de la malla en X","value":0.45075400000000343,"unit":"m","source":"Geometría releída del IFC; datum absoluto de proceso provisional","status":"derivado"},{"label":"Extensión de la malla en Y","value":0.4507539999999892,"unit":"m","source":"Geometría releída del IFC; datum absoluto de proceso provisional","status":"derivado"},{"label":"Extensión de la malla en Z","value":0.020000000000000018,"unit":"m","source":"Geometría releída del IFC; datum absoluto de proceso provisional","status":"derivado"},{"label":"Cota inferior de visualización","value":286.28,"unit":"m","source":"Geometría releída del IFC; datum absoluto de proceso provisional","status":"derivado"},{"label":"Cota superior de visualización","value":286.3,"unit":"m","source":"Geometría releída del IFC; datum absoluto de proceso provisional","status":"derivado"}]} | [] | {"Cota inferior relativa (m)":0.18000000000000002,"Cota superior relativa (m)":0.2,"Cero absoluto de visualización (m)":286.1,"Estado del cero absoluto":"Provisional","Criterio":"Las cotas relativas proceden del dibujo; la equivalencia absoluta no está confirmada."} | SUP-C04 | [] | ["C04"] | ZD1 / DZ-1 | ["2CC59","2CD3E","2CD41","2CD3F","2CD3C","2CD3D","2CD40","2CEAA","2CE85"] | SUP-C04/Cimentación de soporte de tuberías C04 · placa embebida MJ-1 | {"boundingBoxM":{"min":[54.098028,77.288633,1.28],"max":[54.548782,77.739387,1.3]},"extentsM":[0.450754,0.450754,0.02],"meshSurfaceM2":0.352,"meshVolumeM3":0.0032,"closedSolid":true,"basis":"Magnitudes de las mallas representadas, no cantidades certificadas de obra, compra o fabricación. Las partes pueden compartir superficies; no se suman como un despiece de materiales."} | {"elementId":"found_0904_001ba144c99b53","ifcGuid":"2jyuxU1rfS7vxr4YWN$XYW","ifcClass":"IfcPlate","buildingId":"process_plant","buildingName":"Zona de separación de aire","sourceDocumentId":"LHD2609-JG00100-20260904","sourceRepresentationKind":"foundation"} | 2CC59, 2CD3E, 2CD41, 2CD3F, 2CD3C, 2CD3D, 2CD40, 2CEAA, 2CE85 | 0.18 | 0.2 | 0.16 | Contornos y sección documentados por el fabricante | found_0904_001ba144c99b53 | 0.4 | 0.02 | M1: detalle20 mm; MJ1/MJ2:20 mm derivados del contorno lateral80 mm a escala4, no de una cota explícita. | C04 | Fz=-2000 | 15150.0 / 50025.0
Cimentación de soporte de tuberías C05 · placa embebida MJ-1 | 0.450754 | 0.450753 | 0.02 | 286.28 | 286.3 | 0.352 | 0.0032 | {"documentId":"LHD2609-JG00100-20260904","title":"Cimentaciones de equipos y pedestales del fabricante · revisión recibida 04/09/2026","date":"2026-09-04","sheet":"ZD1 / DZ-1","fileName":"LHD2609-JG00100_20260904.dwg","revisionCaveat":"Fecha de revisión tomada del nombre recibido; cajetines internos mantienen 02/07/2026 y algunos textos de plantilla.","sourceFileSha256":"b42eb027b7bc0b14c38d1d13514f4899b58a732aa8d0ba2ccf10fa2fc3192890"} | {"documented":[{"label":"Extensión local X","value":0.4,"unit":"m","source":"2CC5A, 2CD42, 2CC62, 2CC66, 2CC22, 2CC29, 2CD67, 2CEAB, 2CE86","status":"derivada del contorno CAD"},{"label":"Extensión local Y","value":0.4,"unit":"m","source":"2CC5A, 2CD42, 2CC62, 2CC66, 2CC22, 2CC29, 2CD67, 2CEAB, 2CE86","status":"derivada del contorno CAD"},{"label":"Cota inferior relativa adoptada","value":0.18000000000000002,"unit":"m","source":"ZD1 / DZ-1","status":"documentada"},{"label":"Cota superior relativa adoptada","value":0.2,"unit":"m","source":"ZD1 / DZ-1","status":"documentada / separación por material"}],"geometry":[{"label":"Extensión de la malla en X","value":0.45075400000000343,"unit":"m","source":"Geometría releída del IFC; datum absoluto de proceso provisional","status":"derivado"},{"label":"Extensión de la malla en Y","value":0.45075299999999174,"unit":"m","source":"Geometría releída del IFC; datum absoluto de proceso provisional","status":"derivado"},{"label":"Extensión de la malla en Z","value":0.020000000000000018,"unit":"m","source":"Geometría releída del IFC; datum absoluto de proceso provisional","status":"derivado"},{"label":"Cota inferior de visualización","value":286.28,"unit":"m","source":"Geometría releída del IFC; datum absoluto de proceso provisional","status":"derivado"},{"label":"Cota superior de visualización","value":286.3,"unit":"m","source":"Geometría releída del IFC; datum absoluto de proceso provisional","status":"derivado"}]} | [] | {"Cota inferior relativa (m)":0.18000000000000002,"Cota superior relativa (m)":0.2,"Cero absoluto de visualización (m)":286.1,"Estado del cero absoluto":"Provisional","Criterio":"Las cotas relativas proceden del dibujo; la equivalencia absoluta no está confirmada."} | SUP-C05 | [] | ["C05"] | ZD1 / DZ-1 | ["2CC5A","2CD42","2CC62","2CC66","2CC22","2CC29","2CD67","2CEAB","2CE86"] | SUP-C05/Cimentación de soporte de tuberías C05 · placa embebida MJ-1 | {"boundingBoxM":{"min":[60.429392,77.452807,1.28],"max":[60.880146,77.90356,1.3]},"extentsM":[0.450754,0.450753,0.02],"meshSurfaceM2":0.352,"meshVolumeM3":0.0032,"closedSolid":true,"basis":"Magnitudes de las mallas representadas, no cantidades certificadas de obra, compra o fabricación. Las partes pueden compartir superficies; no se suman como un despiece de materiales."} | {"elementId":"found_0904_e56756a93c5322","ifcGuid":"2YOtXN6_1NmhP_CbBBP2Lt","ifcClass":"IfcPlate","buildingId":"process_plant","buildingName":"Zona de separación de aire","sourceDocumentId":"LHD2609-JG00100-20260904","sourceRepresentationKind":"foundation"} | 2CC5A, 2CD42, 2CC62, 2CC66, 2CC22, 2CC29, 2CD67, 2CEAB, 2CE86 | 0.18 | 0.2 | 0.16 | Contornos y sección documentados por el fabricante | found_0904_e56756a93c5322 | 0.4 | 0.02 | M1: detalle20 mm; MJ1/MJ2:20 mm derivados del contorno lateral80 mm a escala4, no de una cota explícita. | C05 | Fz=-1500 | 21400.0 / 51050.0
Cimentación de soporte de tuberías C06 · placa embebida MJ-1 | 0.450754 | 0.450754 | 0.02 | 286.28 | 286.3 | 0.352 | 0.0032 | {"documentId":"LHD2609-JG00100-20260904","title":"Cimentaciones de equipos y pedestales del fabricante · revisión recibida 04/09/2026","date":"2026-09-04","sheet":"ZD1 / DZ-1","fileName":"LHD2609-JG00100_20260904.dwg","revisionCaveat":"Fecha de revisión tomada del nombre recibido; cajetines internos mantienen 02/07/2026 y algunos textos de plantilla.","sourceFileSha256":"b42eb027b7bc0b14c38d1d13514f4899b58a732aa8d0ba2ccf10fa2fc3192890"} | {"documented":[{"label":"Extensión local X","value":0.4,"unit":"m","source":"2CC5B, 2CD43, 2CC63, 2CC67, 2CC23, 2CC2A, 2CD68, 2CEAC, 2CE87","status":"derivada del contorno CAD"},{"label":"Extensión local Y","value":0.4,"unit":"m","source":"2CC5B, 2CD43, 2CC63, 2CC67, 2CC23, 2CC2A, 2CD68, 2CEAC, 2CE87","status":"derivada del contorno CAD"},{"label":"Cota inferior relativa adoptada","value":0.18000000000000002,"unit":"m","source":"ZD1 / DZ-1","status":"documentada"},{"label":"Cota superior relativa adoptada","value":0.2,"unit":"m","source":"ZD1 / DZ-1","status":"documentada / separación por material"}],"geometry":[{"label":"Extensión de la malla en X","value":0.45075400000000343,"unit":"m","source":"Geometría releída del IFC; datum absoluto de proceso provisional","status":"derivado"},{"label":"Extensión de la malla en Y","value":0.45075400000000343,"unit":"m","source":"Geometría releída del IFC; datum absoluto de proceso provisional","status":"derivado"},{"label":"Extensión de la malla en Z","value":0.020000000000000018,"unit":"m","source":"Geometría releída del IFC; datum absoluto de proceso provisional","status":"derivado"},{"label":"Cota inferior de visualización","value":286.28,"unit":"m","source":"Geometría releída del IFC; datum absoluto de proceso provisional","status":"derivado"},{"label":"Cota superior de visualización","value":286.3,"unit":"m","source":"Geometría releída del IFC; datum absoluto de proceso provisional","status":"derivado"}]} | [] | {"Cota inferior relativa (m)":0.18000000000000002,"Cota superior relativa (m)":0.2,"Cero absoluto de visualización (m)":286.1,"Estado del cero absoluto":"Provisional","Criterio":"Las cotas relativas proceden del dibujo; la equivalencia absoluta no está confirmada."} | SUP-C06 | [] | ["C06"] | ZD1 / DZ-1 | ["2CC5B","2CD43","2CC63","2CC67","2CC23","2CC2A","2CD68","2CEAC","2CE87"] | SUP-C06/Cimentación de soporte de tuberías C06 · placa embebida MJ-1 | {"boundingBoxM":{"min":[60.289783,76.437359,1.28],"max":[60.740537,76.888113,1.3]},"extentsM":[0.450754,0.450754,0.02],"meshSurfaceM2":0.352,"meshVolumeM3":0.0032,"closedSolid":true,"basis":"Magnitudes de las mallas representadas, no cantidades certificadas de obra, compra o fabricación. Las partes pueden compartir superficies; no se suman como un despiece de materiales."} | {"elementId":"found_0904_7d19a048c11798","ifcGuid":"1hf9DkADvKWOQzZL5jZulo","ifcClass":"IfcPlate","buildingId":"process_plant","buildingName":"Zona de separación de aire","sourceDocumentId":"LHD2609-JG00100-20260904","sourceRepresentationKind":"foundation"} | 2CC5B, 2CD43, 2CC63, 2CC67, 2CC23, 2CC2A, 2CD68, 2CEAC, 2CE87 | 0.18 | 0.2 | 0.16 | Contornos y sección documentados por el fabricante | found_0904_7d19a048c11798 | 0.4 | 0.02 | M1: detalle20 mm; MJ1/MJ2:20 mm derivados del contorno lateral80 mm a escala4, no de una cota explícita. | C06 | Fz=-1500 | 21400.0 / 50025.0
Cimentación de soporte de tuberías C07 · placa embebida MJ-1 | 0.450754 | 0.450754 | 0.02 | 286.28 | 286.3 | 0.352 | 0.0032 | {"documentId":"LHD2609-JG00100-20260904","title":"Cimentaciones de equipos y pedestales del fabricante · revisión recibida 04/09/2026","date":"2026-09-04","sheet":"ZD1 / DZ-1","fileName":"LHD2609-JG00100_20260904.dwg","revisionCaveat":"Fecha de revisión tomada del nombre recibido; cajetines internos mantienen 02/07/2026 y algunos textos de plantilla.","sourceFileSha256":"b42eb027b7bc0b14c38d1d13514f4899b58a732aa8d0ba2ccf10fa2fc3192890"} | {"documented":[{"label":"Extensión local X","value":0.4,"unit":"m","source":"2CC5C, 2CD44, 2CC60, 2CC68, 2CC24, 2CC2B, 2CD69, 2CEAD, 2CE88","status":"derivada del contorno CAD"},{"label":"Extensión local Y","value":0.4,"unit":"m","source":"2CC5C, 2CD44, 2CC60, 2CC68, 2CC24, 2CC2B, 2CD69, 2CEAD, 2CE88","status":"derivada del contorno CAD"},{"label":"Cota inferior relativa adoptada","value":0.18000000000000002,"unit":"m","source":"ZD1 / DZ-1","status":"documentada"},{"label":"Cota superior relativa adoptada","value":0.2,"unit":"m","source":"ZD1 / DZ-1","status":"documentada / separación por material"}],"geometry":[{"label":"Extensión de la malla en X","value":0.4507539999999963,"unit":"m","source":"Geometría releída del IFC; datum absoluto de proceso provisional","status":"derivado"},{"label":"Extensión de la malla en Y","value":0.45075400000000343,"unit":"m","source":"Geometría releída del IFC; datum absoluto de proceso provisional","status":"derivado"},{"label":"Extensión de la malla en Z","value":0.020000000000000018,"unit":"m","source":"Geometría releída del IFC; datum absoluto de proceso provisional","status":"derivado"},{"label":"Cota inferior de visualización","value":286.28,"unit":"m","source":"Geometría releída del IFC; datum absoluto de proceso provisional","status":"derivado"},{"label":"Cota superior de visualización","value":286.3,"unit":"m","source":"Geometría releída del IFC; datum absoluto de proceso provisional","status":"derivado"}]} | [] | {"Cota inferior relativa (m)":0.18000000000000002,"Cota superior relativa (m)":0.2,"Cero absoluto de visualización (m)":286.1,"Estado del cero absoluto":"Provisional","Criterio":"Las cotas relativas proceden del dibujo; la equivalencia absoluta no está confirmada."} | SUP-C07 | [] | ["C07"] | ZD1 / DZ-1 | ["2CC5C","2CD44","2CC60","2CC68","2CC24","2CC2B","2CD69","2CEAD","2CE88"] | SUP-C07/Cimentación de soporte de tuberías C07 · placa embebida MJ-1 | {"boundingBoxM":{"min":[45.725903,74.578695,1.28],"max":[46.176657,75.029449,1.3]},"extentsM":[0.450754,0.450754,0.02],"meshSurfaceM2":0.352,"meshVolumeM3":0.0032,"closedSolid":true,"basis":"Magnitudes de las mallas representadas, no cantidades certificadas de obra, compra o fabricación. Las partes pueden compartir superficies; no se suman como un despiece de materiales."} | {"elementId":"found_0904_1d53cfb54d6daf","ifcGuid":"3CMT85CAfRbgd8AmfmXWPn","ifcClass":"IfcPlate","buildingId":"process_plant","buildingName":"Zona de separación de aire","sourceDocumentId":"LHD2609-JG00100-20260904","sourceRepresentationKind":"foundation"} | 2CC5C, 2CD44, 2CC60, 2CC68, 2CC24, 2CC2B, 2CD69, 2CEAD, 2CE88 | 0.18 | 0.2 | 0.16 | Contornos y sección documentados por el fabricante | found_0904_1d53cfb54d6daf | 0.4 | 0.02 | M1: detalle20 mm; MJ1/MJ2:20 mm derivados del contorno lateral80 mm a escala4, no de una cota explícita. | C07 | Fz=-2000 | 7225.0 / 46200.0
Cimentación de soporte de tuberías C08 · placa embebida MJ-1 | 0.450754 | 0.450754 | 0.02 | 286.28 | 286.3 | 0.352 | 0.0032 | {"documentId":"LHD2609-JG00100-20260904","title":"Cimentaciones de equipos y pedestales del fabricante · revisión recibida 04/09/2026","date":"2026-09-04","sheet":"ZD1 / DZ-1","fileName":"LHD2609-JG00100_20260904.dwg","revisionCaveat":"Fecha de revisión tomada del nombre recibido; cajetines internos mantienen 02/07/2026 y algunos textos de plantilla.","sourceFileSha256":"b42eb027b7bc0b14c38d1d13514f4899b58a732aa8d0ba2ccf10fa2fc3192890"} | {"documented":[{"label":"Extensión local X","value":0.4,"unit":"m","source":"2CC5D, 2CD45, 2CC61, 2CC69, 2CC25, 2CC2C, 2CD6A, 2CEAE, 2CE89","status":"derivada del contorno CAD"},{"label":"Extensión local Y","value":0.4,"unit":"m","source":"2CC5D, 2CD45, 2CC61, 2CC69, 2CC25, 2CC2C, 2CD6A, 2CEAE, 2CE89","status":"derivada del contorno CAD"},{"label":"Cota inferior relativa adoptada","value":0.18000000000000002,"unit":"m","source":"ZD1 / DZ-1","status":"documentada"},{"label":"Cota superior relativa adoptada","value":0.2,"unit":"m","source":"ZD1 / DZ-1","status":"documentada / separación por material"}],"geometry":[{"label":"Extensión de la malla en X","value":0.4507539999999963,"unit":"m","source":"Geometría releída del IFC; datum absoluto de proceso provisional","status":"derivado"},{"label":"Extensión de la malla en Y","value":0.45075400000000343,"unit":"m","source":"Geometría releída del IFC; datum absoluto de proceso provisional","status":"derivado"},{"label":"Extensión de la malla en Z","value":0.020000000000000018,"unit":"m","source":"Geometría releída del IFC; datum absoluto de proceso provisional","status":"derivado"},{"label":"Cota inferior de visualización","value":286.28,"unit":"m","source":"Geometría releída del IFC; datum absoluto de proceso provisional","status":"derivado"},{"label":"Cota superior de visualización","value":286.3,"unit":"m","source":"Geometría releída del IFC; datum absoluto de proceso provisional","status":"derivado"}]} | [] | {"Cota inferior relativa (m)":0.18000000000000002,"Cota superior relativa (m)":0.2,"Cero absoluto de visualización (m)":286.1,"Estado del cero absoluto":"Provisional","Criterio":"Las cotas relativas proceden del dibujo; la equivalencia absoluta no está confirmada."} | SUP-C08 | [] | ["C08"] | ZD1 / DZ-1 | ["2CC5D","2CD45","2CC61","2CC69","2CC25","2CC2C","2CD6A","2CEAE","2CE89"] | SUP-C08/Cimentación de soporte de tuberías C08 · placa embebida MJ-1 | {"boundingBoxM":{"min":[46.865186,74.422061,1.28],"max":[47.31594,74.872815,1.3]},"extentsM":[0.450754,0.450754,0.02],"meshSurfaceM2":0.352,"meshVolumeM3":0.0032,"closedSolid":true,"basis":"Magnitudes de las mallas representadas, no cantidades certificadas de obra, compra o fabricación. Las partes pueden compartir superficies; no se suman como un despiece de materiales."} | {"elementId":"found_0904_67cbe0f5a4206a","ifcGuid":"2BMICAW7LKTOtfEIR$oUVu","ifcClass":"IfcPlate","buildingId":"process_plant","buildingName":"Zona de separación de aire","sourceDocumentId":"LHD2609-JG00100-20260904","sourceRepresentationKind":"foundation"} | 2CC5D, 2CD45, 2CC61, 2CC69, 2CC25, 2CC2C, 2CD6A, 2CEAE, 2CE89 | 0.18 | 0.2 | 0.16 | Contornos y sección documentados por el fabricante | found_0904_67cbe0f5a4206a | 0.4 | 0.02 | M1: detalle20 mm; MJ1/MJ2:20 mm derivados del contorno lateral80 mm a escala4, no de una cota explícita. | C08 | Fz=-2000 | 8375.0 / 46200.0
Cimentación de soporte de tuberías C09 · placa embebida MJ-1 | 0.450754 | 0.450754 | 0.02 | 286.28 | 286.3 | 0.352 | 0.0032 | {"documentId":"LHD2609-JG00100-20260904","title":"Cimentaciones de equipos y pedestales del fabricante · revisión recibida 04/09/2026","date":"2026-09-04","sheet":"ZD1 / DZ-1","fileName":"LHD2609-JG00100_20260904.dwg","revisionCaveat":"Fecha de revisión tomada del nombre recibido; cajetines internos mantienen 02/07/2026 y algunos textos de plantilla.","sourceFileSha256":"b42eb027b7bc0b14c38d1d13514f4899b58a732aa8d0ba2ccf10fa2fc3192890"} | {"documented":[{"label":"Extensión local X","value":0.4,"unit":"m","source":"2CC5E, 2CD46, 2CDAA, 2CC6A, 2CC26, 2CC2D, 2CD6B, 2CEAF, 2CE8A","status":"derivada del contorno CAD"},{"label":"Extensión local Y","value":0.4,"unit":"m","source":"2CC5E, 2CD46, 2CDAA, 2CC6A, 2CC26, 2CC2D, 2CD6B, 2CEAF, 2CE8A","status":"derivada del contorno CAD"},{"label":"Cota inferior relativa adoptada","value":0.18000000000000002,"unit":"m","source":"ZD1 / DZ-1","status":"documentada"},{"label":"Cota superior relativa adoptada","value":0.2,"unit":"m","source":"ZD1 / DZ-1","status":"documentada / separación por material"}],"geometry":[{"label":"Extensión de la malla en X","value":0.45075400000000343,"unit":"m","source":"Geometría releída del IFC; datum absoluto de proceso provisional","status":"derivado"},{"label":"Extensión de la malla en Y","value":0.4507539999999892,"unit":"m","source":"Geometría releída del IFC; datum absoluto de proceso provisional","status":"derivado"},{"label":"Extensión de la malla en Z","value":0.020000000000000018,"unit":"m","source":"Geometría releída del IFC; datum absoluto de proceso provisional","status":"derivado"},{"label":"Cota inferior de visualización","value":286.28,"unit":"m","source":"Geometría releída del IFC; datum absoluto de proceso provisional","status":"derivado"},{"label":"Cota superior de visualización","value":286.3,"unit":"m","source":"Geometría releída del IFC; datum absoluto de proceso provisional","status":"derivado"}]} | [] | {"Cota inferior relativa (m)":0.18000000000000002,"Cota superior relativa (m)":0.2,"Cero absoluto de visualización (m)":286.1,"Estado del cero absoluto":"Provisional","Criterio":"Las cotas relativas proceden del dibujo; la equivalencia absoluta no está confirmada."} | SUP-C09 | [] | ["C09"] | ZD1 / DZ-1 | ["2CC5E","2CD46","2CDAA","2CC6A","2CC26","2CC2D","2CD6B","2CEAF","2CE8A"] | SUP-C09/Cimentación de soporte de tuberías C09 · placa embebida MJ-1 | {"boundingBoxM":{"min":[45.044883,69.625291,1.28],"max":[45.495637,70.076045,1.3]},"extentsM":[0.450754,0.450754,0.02],"meshSurfaceM2":0.352,"meshVolumeM3":0.0032,"closedSolid":true,"basis":"Magnitudes de las mallas representadas, no cantidades certificadas de obra, compra o fabricación. Las partes pueden compartir superficies; no se suman como un despiece de materiales."} | {"elementId":"found_0904_9bf857aac02af7","ifcGuid":"18ErsS$XrSLfmciWwQVEK5","ifcClass":"IfcPlate","buildingId":"process_plant","buildingName":"Zona de separación de aire","sourceDocumentId":"LHD2609-JG00100-20260904","sourceRepresentationKind":"foundation"} | 2CC5E, 2CD46, 2CDAA, 2CC6A, 2CC26, 2CC2D, 2CD6B, 2CEAF, 2CE8A | 0.18 | 0.2 | 0.16 | Contornos y sección documentados por el fabricante | found_0904_9bf857aac02af7 | 0.4 | 0.02 | M1: detalle20 mm; MJ1/MJ2:20 mm derivados del contorno lateral80 mm a escala4, no de una cota explícita. | C09 | Fz=-2000 | 7225.0 / 41200.0
Cimentación de soporte de tuberías C10 · placa embebida MJ-1 | 0.450754 | 0.450753 | 0.02 | 286.28 | 286.3 | 0.351999 | 0.0032 | {"documentId":"LHD2609-JG00100-20260904","title":"Cimentaciones de equipos y pedestales del fabricante · revisión recibida 04/09/2026","date":"2026-09-04","sheet":"ZD1 / DZ-1","fileName":"LHD2609-JG00100_20260904.dwg","revisionCaveat":"Fecha de revisión tomada del nombre recibido; cajetines internos mantienen 02/07/2026 y algunos textos de plantilla.","sourceFileSha256":"b42eb027b7bc0b14c38d1d13514f4899b58a732aa8d0ba2ccf10fa2fc3192890"} | {"documented":[{"label":"Extensión local X","value":0.4,"unit":"m","source":"2CC5F, 2CD47, 2CDAB, 2CC6B, 2CC27, 2CC2E, 2CD6C, 2CEB0, 2CE8B","status":"derivada del contorno CAD"},{"label":"Extensión local Y","value":0.4,"unit":"m","source":"2CC5F, 2CD47, 2CDAB, 2CC6B, 2CC27, 2CC2E, 2CD6C, 2CEB0, 2CE8B","status":"derivada del contorno CAD"},{"label":"Cota inferior relativa adoptada","value":0.18000000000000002,"unit":"m","source":"ZD1 / DZ-1","status":"documentada"},{"label":"Cota superior relativa adoptada","value":0.2,"unit":"m","source":"ZD1 / DZ-1","status":"documentada / separación por material"}],"geometry":[{"label":"Extensión de la malla en X","value":0.45075400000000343,"unit":"m","source":"Geometría releída del IFC; datum absoluto de proceso provisional","status":"derivado"},{"label":"Extensión de la malla en Y","value":0.45075300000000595,"unit":"m","source":"Geometría releída del IFC; datum absoluto de proceso provisional","status":"derivado"},{"label":"Extensión de la malla en Z","value":0.020000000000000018,"unit":"m","source":"Geometría releída del IFC; datum absoluto de proceso provisional","status":"derivado"},{"label":"Cota inferior de visualización","value":286.28,"unit":"m","source":"Geometría releída del IFC; datum absoluto de proceso provisional","status":"derivado"},{"label":"Cota superior de visualización","value":286.3,"unit":"m","source":"Geometría releída del IFC; datum absoluto de proceso provisional","status":"derivado"}]} | [] | {"Cota inferior relativa (m)":0.18000000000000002,"Cota superior relativa (m)":0.2,"Cero absoluto de visualización (m)":286.1,"Estado del cero absoluto":"Provisional","Criterio":"Las cotas relativas proceden del dibujo; la equivalencia absoluta no está confirmada."} | SUP-C10 | [] | ["C10"] | ZD1 / DZ-1 | ["2CC5F","2CD47","2CDAB","2CC6B","2CC27","2CC2E","2CD6C","2CEB0","2CE8B"] | SUP-C10/Cimentación de soporte de tuberías C10 · placa embebida MJ-1 | {"boundingBoxM":{"min":[46.184166,69.468657,1.28],"max":[46.63492,69.91941,1.3]},"extentsM":[0.450754,0.450753,0.02],"meshSurfaceM2":0.351999,"meshVolumeM3":0.0032,"closedSolid":true,"basis":"Magnitudes de las mallas representadas, no cantidades certificadas de obra, compra o fabricación. Las partes pueden compartir superficies; no se suman como un despiece de materiales."} | {"elementId":"found_0904_e3d61feae81753","ifcGuid":"3wMnFiwTvPgOiCKzeAWv4Q","ifcClass":"IfcPlate","buildingId":"process_plant","buildingName":"Zona de separación de aire","sourceDocumentId":"LHD2609-JG00100-20260904","sourceRepresentationKind":"foundation"} | 2CC5F, 2CD47, 2CDAB, 2CC6B, 2CC27, 2CC2E, 2CD6C, 2CEB0, 2CE8B | 0.18 | 0.2 | 0.16 | Contornos y sección documentados por el fabricante | found_0904_e3d61feae81753 | 0.4 | 0.02 | M1: detalle20 mm; MJ1/MJ2:20 mm derivados del contorno lateral80 mm a escala4, no de una cota explícita. | C10 | Fz=-2000 | 8375.0 / 41200.0
Cimentación de soporte de tuberías C11 · placa embebida MJ-1 | 0.450754 | 0.450754 | 0.02 | 286.28 | 286.3 | 0.352 | 0.0032 | {"documentId":"LHD2609-JG00100-20260904","title":"Cimentaciones de equipos y pedestales del fabricante · revisión recibida 04/09/2026","date":"2026-09-04","sheet":"ZD1 / DZ-1","fileName":"LHD2609-JG00100_20260904.dwg","revisionCaveat":"Fecha de revisión tomada del nombre recibido; cajetines internos mantienen 02/07/2026 y algunos textos de plantilla.","sourceFileSha256":"b42eb027b7bc0b14c38d1d13514f4899b58a732aa8d0ba2ccf10fa2fc3192890"} | {"documented":[{"label":"Extensión local X","value":0.4,"unit":"m","source":"2CC77, 2CD48, 2CDAC, 2CC78, 2CC73, 2CC74, 2CD6D, 2CEB1, 2CE8C","status":"derivada del contorno CAD"},{"label":"Extensión local Y","value":0.4,"unit":"m","source":"2CC77, 2CD48, 2CDAC, 2CC78, 2CC73, 2CC74, 2CD6D, 2CEB1, 2CE8C","status":"derivada del contorno CAD"},{"label":"Cota inferior relativa adoptada","value":0.18000000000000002,"unit":"m","source":"ZD1 / DZ-1","status":"documentada"},{"label":"Cota superior relativa adoptada","value":0.2,"unit":"m","source":"ZD1 / DZ-1","status":"documentada / separación por material"}],"geometry":[{"label":"Extensión de la malla en X","value":0.4507539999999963,"unit":"m","source":"Geometría releída del IFC; datum absoluto de proceso provisional","status":"derivado"},{"label":"Extensión de la malla en Y","value":0.45075400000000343,"unit":"m","source":"Geometría releída del IFC; datum absoluto de proceso provisional","status":"derivado"},{"label":"Extensión de la malla en Z","value":0.020000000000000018,"unit":"m","source":"Geometría releída del IFC; datum absoluto de proceso provisional","status":"derivado"},{"label":"Cota inferior de visualización","value":286.28,"unit":"m","source":"Geometría releída del IFC; datum absoluto de proceso provisional","status":"derivado"},{"label":"Cota superior de visualización","value":286.3,"unit":"m","source":"Geometría releída del IFC; datum absoluto de proceso provisional","status":"derivado"}]} | [] | {"Cota inferior relativa (m)":0.18000000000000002,"Cota superior relativa (m)":0.2,"Cero absoluto de visualización (m)":286.1,"Estado del cero absoluto":"Provisional","Criterio":"Las cotas relativas proceden del dibujo; la equivalencia absoluta no está confirmada."} | SUP-C11 | [] | ["C11"] | ZD1 / DZ-1 | ["2CC77","2CD48","2CDAC","2CC78","2CC73","2CC74","2CD6D","2CEB1","2CE8C"] | SUP-C11/Cimentación de soporte de tuberías C11 · placa embebida MJ-1 | {"boundingBoxM":{"min":[44.363863,64.671887,1.28],"max":[44.814617,65.122641,1.3]},"extentsM":[0.450754,0.450754,0.02],"meshSurfaceM2":0.352,"meshVolumeM3":0.0032,"closedSolid":true,"basis":"Magnitudes de las mallas representadas, no cantidades certificadas de obra, compra o fabricación. Las partes pueden compartir superficies; no se suman como un despiece de materiales."} | {"elementId":"found_0904_dac4964c2ca873","ifcGuid":"24wf61dBzKcx_CDxvZHgke","ifcClass":"IfcPlate","buildingId":"process_plant","buildingName":"Zona de separación de aire","sourceDocumentId":"LHD2609-JG00100-20260904","sourceRepresentationKind":"foundation"} | 2CC77, 2CD48, 2CDAC, 2CC78, 2CC73, 2CC74, 2CD6D, 2CEB1, 2CE8C | 0.18 | 0.2 | 0.16 | Contornos y sección documentados por el fabricante | found_0904_dac4964c2ca873 | 0.4 | 0.02 | M1: detalle20 mm; MJ1/MJ2:20 mm derivados del contorno lateral80 mm a escala4, no de una cota explícita. | C11 | Fz=-2000 | 7225.0 / 36200.0
Cimentación de soporte de tuberías C12 · placa embebida MJ-1 | 0.450754 | 0.450754 | 0.02 | 286.28 | 286.3 | 0.352 | 0.0032 | {"documentId":"LHD2609-JG00100-20260904","title":"Cimentaciones de equipos y pedestales del fabricante · revisión recibida 04/09/2026","date":"2026-09-04","sheet":"ZD1 / DZ-1","fileName":"LHD2609-JG00100_20260904.dwg","revisionCaveat":"Fecha de revisión tomada del nombre recibido; cajetines internos mantienen 02/07/2026 y algunos textos de plantilla.","sourceFileSha256":"b42eb027b7bc0b14c38d1d13514f4899b58a732aa8d0ba2ccf10fa2fc3192890"} | {"documented":[{"label":"Extensión local X","value":0.4,"unit":"m","source":"2CC7D, 2CD49, 2CDA8, 2CC7E, 2CC79, 2CC7A, 2CD6E, 2CEB2, 2CE8D","status":"derivada del contorno CAD"},{"label":"Extensión local Y","value":0.4,"unit":"m","source":"2CC7D, 2CD49, 2CDA8, 2CC7E, 2CC79, 2CC7A, 2CD6E, 2CEB2, 2CE8D","status":"derivada del contorno CAD"},{"label":"Cota inferior relativa adoptada","value":0.18000000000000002,"unit":"m","source":"ZD1 / DZ-1","status":"documentada"},{"label":"Cota superior relativa adoptada","value":0.2,"unit":"m","source":"ZD1 / DZ-1","status":"documentada / separación por material"}],"geometry":[{"label":"Extensión de la malla en X","value":0.4507539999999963,"unit":"m","source":"Geometría releída del IFC; datum absoluto de proceso provisional","status":"derivado"},{"label":"Extensión de la malla en Y","value":0.4507539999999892,"unit":"m","source":"Geometría releída del IFC; datum absoluto de proceso provisional","status":"derivado"},{"label":"Extensión de la malla en Z","value":0.020000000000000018,"unit":"m","source":"Geometría releída del IFC; datum absoluto de proceso provisional","status":"derivado"},{"label":"Cota inferior de visualización","value":286.28,"unit":"m","source":"Geometría releída del IFC; datum absoluto de proceso provisional","status":"derivado"},{"label":"Cota superior de visualización","value":286.3,"unit":"m","source":"Geometría releída del IFC; datum absoluto de proceso provisional","status":"derivado"}]} | [] | {"Cota inferior relativa (m)":0.18000000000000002,"Cota superior relativa (m)":0.2,"Cero absoluto de visualización (m)":286.1,"Estado del cero absoluto":"Provisional","Criterio":"Las cotas relativas proceden del dibujo; la equivalencia absoluta no está confirmada."} | SUP-C12 | [] | ["C12"] | ZD1 / DZ-1 | ["2CC7D","2CD49","2CDA8","2CC7E","2CC79","2CC7A","2CD6E","2CEB2","2CE8D"] | SUP-C12/Cimentación de soporte de tuberías C12 · placa embebida MJ-1 | {"boundingBoxM":{"min":[45.503146,64.515252,1.28],"max":[45.9539,64.966006,1.3]},"extentsM":[0.450754,0.450754,0.02],"meshSurfaceM2":0.352,"meshVolumeM3":0.0032,"closedSolid":true,"basis":"Magnitudes de las mallas representadas, no cantidades certificadas de obra, compra o fabricación. Las partes pueden compartir superficies; no se suman como un despiece de materiales."} | {"elementId":"found_0904_e3b74ddf869bf0","ifcGuid":"1Q5boagCjTRPB6gXp0d27O","ifcClass":"IfcPlate","buildingId":"process_plant","buildingName":"Zona de separación de aire","sourceDocumentId":"LHD2609-JG00100-20260904","sourceRepresentationKind":"foundation"} | 2CC7D, 2CD49, 2CDA8, 2CC7E, 2CC79, 2CC7A, 2CD6E, 2CEB2, 2CE8D | 0.18 | 0.2 | 0.16 | Contornos y sección documentados por el fabricante | found_0904_e3b74ddf869bf0 | 0.4 | 0.02 | M1: detalle20 mm; MJ1/MJ2:20 mm derivados del contorno lateral80 mm a escala4, no de una cota explícita. | C12 | Fz=-2000 | 8375.0 / 36200.0
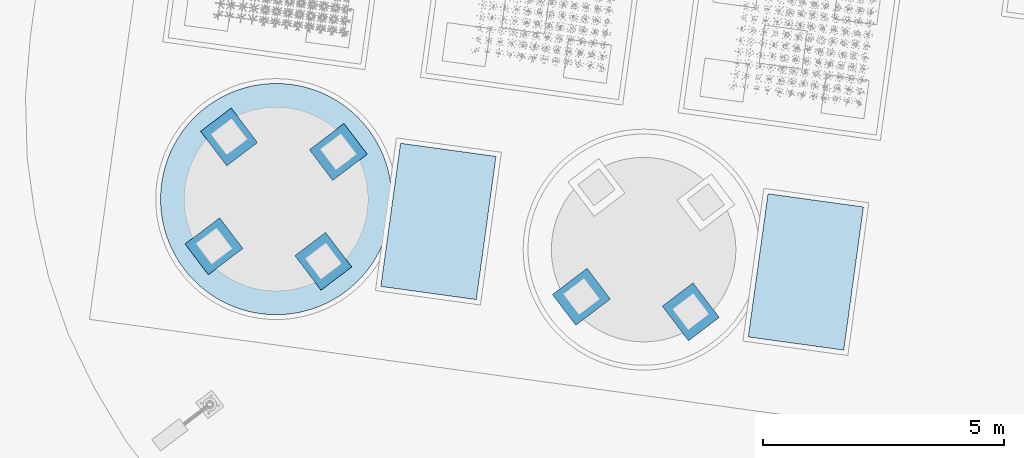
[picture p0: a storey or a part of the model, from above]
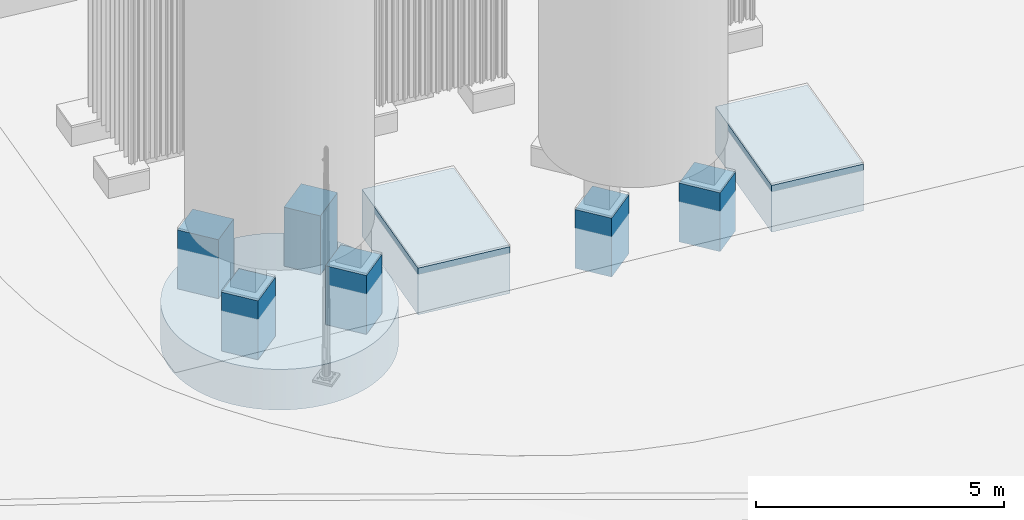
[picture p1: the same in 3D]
Properties of the parts of a building model (IFC4), part 99 of 134

# IfcPlate: Cimentación industrial (48)
Name | Extensión de la malla en X (m) = ExtensionX (m) | Extensión de la malla en Y (m) = ExtensionY (m) | Extensión de la malla en Z (m) = ExtensionZ (m) = Espesor o altura real de sección (m) | Cota inferior de visualización (m) | Cota superior de visualización (m) | SuperficieDeLaMalla (m2) | VolumenGeometrico (m3) = Volumen geométrico (m³) | source = DocumentoFuente | dimensions | issues = IncidenciasPendientes | positioning = PosicionYEstado | assemblyId = Conjunto de cimentación | equipmentIds | supportPositionIds | sectionRef = Sección de referencia | sourceCadHandles | stableElementKey | geometryMetrics | visualizationIdentity | Identificadores CAD de referencia | Cota inferior relativa (m) = Cota inferior relativa adoptada (m) | Cota superior relativa (m) = Cota superior relativa adoptada (m) | Área de planta (m²) | Estado de la geometría | Identificador | Extensión local X (m) = Extensión local Y (m) | Espesor de placa (m) | Origen del espesor de placa | Código original en tabla | Carga vertical indicada | Posición E/N de la tabla (mm)
Cimentación de soporte de tuberías C13 · placa embebida MJ-1 | 0.450754 | 0.450754 | 0.02 | 286.28 | 286.3 | 0.352 | 0.0032 | {"documentId":"LHD2609-JG00100-20260904","title":"Cimentaciones de equipos y pedestales del fabricante · revisión recibida 04/09/2026","date":"2026-09-04","sheet":"ZD1 / DZ-1","fileName":"LHD2609-JG00100_20260904.dwg","revisionCaveat":"Fecha de revisión tomada del nombre recibido; cajetines internos mantienen 02/07/2026 y algunos textos de plantilla.","sourceFileSha256":"b42eb027b7bc0b14c38d1d13514f4899b58a732aa8d0ba2ccf10fa2fc3192890"} | {"documented":[{"label":"Extensión local X","value":0.4,"unit":"m","source":"2CC83, 2CD4A, 2CDA9, 2CC84, 2CC7F, 2CC80, 2CD6F, 2CEB3, 2CE8E","status":"derivada del contorno CAD"},{"label":"Extensión local Y","value":0.4,"unit":"m","source":"2CC83, 2CD4A, 2CDA9, 2CC84, 2CC7F, 2CC80, 2CD6F, 2CEB3, 2CE8E","status":"derivada del contorno CAD"},{"label":"Cota inferior relativa adoptada","value":0.18000000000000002,"unit":"m","source":"ZD1 / DZ-1","status":"documentada"},{"label":"Cota superior relativa adoptada","value":0.2,"unit":"m","source":"ZD1 / DZ-1","status":"documentada / separación por material"}],"geometry":[{"label":"Extensión de la malla en X","value":0.45075400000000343,"unit":"m","source":"Geometría releída del IFC; datum absoluto de proceso provisional","status":"derivado"},{"label":"Extensión de la malla en Y","value":0.4507539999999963,"unit":"m","source":"Geometría releída del IFC; datum absoluto de proceso provisional","status":"derivado"},{"label":"Extensión de la malla en Z","value":0.020000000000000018,"unit":"m","source":"Geometría releída del IFC; datum absoluto de proceso provisional","status":"derivado"},{"label":"Cota inferior de visualización","value":286.28,"unit":"m","source":"Geometría releída del IFC; datum absoluto de proceso provisional","status":"derivado"},{"label":"Cota superior de visualización","value":286.3,"unit":"m","source":"Geometría releída del IFC; datum absoluto de proceso provisional","status":"derivado"}]} | [] | {"Cota inferior relativa (m)":0.18000000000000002,"Cota superior relativa (m)":0.2,"Cero absoluto de visualización (m)":286.1,"Estado del cero absoluto":"Provisional","Criterio":"Las cotas relativas proceden del dibujo; la equivalencia absoluta no está confirmada."} | SUP-C13 | [] | ["C13"] | ZD1 / DZ-1 | ["2CC83","2CD4A","2CDA9","2CC84","2CC7F","2CC80","2CD6F","2CEB3","2CE8E"] | SUP-C13/Cimentación de soporte de tuberías C13 · placa embebida MJ-1 | {"boundingBoxM":{"min":[43.614742,59.223142,1.28],"max":[44.065496,59.673896,1.3]},"extentsM":[0.450754,0.450754,0.02],"meshSurfaceM2":0.352,"meshVolumeM3":0.0032,"closedSolid":true,"basis":"Magnitudes de las mallas representadas, no cantidades certificadas de obra, compra o fabricación. Las partes pueden compartir superficies; no se suman como un despiece de materiales."} | {"elementId":"found_0904_1aa96091deac75","ifcGuid":"0i_FenxbDHpRlgEuvAXz$x","ifcClass":"IfcPlate","buildingId":"process_plant","buildingName":"Zona de separación de aire","sourceDocumentId":"LHD2609-JG00100-20260904","sourceRepresentationKind":"foundation"} | 2CC83, 2CD4A, 2CDA9, 2CC84, 2CC7F, 2CC80, 2CD6F, 2CEB3, 2CE8E | 0.18 | 0.2 | 0.16 | Contornos y sección documentados por el fabricante | found_0904_1aa96091deac75 | 0.4 | 0.02 | M1: detalle20 mm; MJ1/MJ2:20 mm derivados del contorno lateral80 mm a escala4, no de una cota explícita. | C13 | Fz=-2000 | 7225.0 / 30700.0
Cimentación de soporte de tuberías C14 · placa embebida MJ-1 | 0.450754 | 0.450754 | 0.02 | 286.28 | 286.3 | 0.352 | 0.0032 | {"documentId":"LHD2609-JG00100-20260904","title":"Cimentaciones de equipos y pedestales del fabricante · revisión recibida 04/09/2026","date":"2026-09-04","sheet":"ZD1 / DZ-1","fileName":"LHD2609-JG00100_20260904.dwg","revisionCaveat":"Fecha de revisión tomada del nombre recibido; cajetines internos mantienen 02/07/2026 y algunos textos de plantilla.","sourceFileSha256":"b42eb027b7bc0b14c38d1d13514f4899b58a732aa8d0ba2ccf10fa2fc3192890"} | {"documented":[{"label":"Extensión local X","value":0.4,"unit":"m","source":"2CC89, 2CD4B, 2CDA7, 2CC8A, 2CC85, 2CC86, 2CD70, 2CEB4, 2CE8F","status":"derivada del contorno CAD"},{"label":"Extensión local Y","value":0.4,"unit":"m","source":"2CC89, 2CD4B, 2CDA7, 2CC8A, 2CC85, 2CC86, 2CD70, 2CEB4, 2CE8F","status":"derivada del contorno CAD"},{"label":"Cota inferior relativa adoptada","value":0.18000000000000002,"unit":"m","source":"ZD1 / DZ-1","status":"documentada"},{"label":"Cota superior relativa adoptada","value":0.2,"unit":"m","source":"ZD1 / DZ-1","status":"documentada / separación por material"}],"geometry":[{"label":"Extensión de la malla en X","value":0.45075400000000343,"unit":"m","source":"Geometría releída del IFC; datum absoluto de proceso provisional","status":"derivado"},{"label":"Extensión de la malla en Y","value":0.45075400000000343,"unit":"m","source":"Geometría releída del IFC; datum absoluto de proceso provisional","status":"derivado"},{"label":"Extensión de la malla en Z","value":0.020000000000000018,"unit":"m","source":"Geometría releída del IFC; datum absoluto de proceso provisional","status":"derivado"},{"label":"Cota inferior de visualización","value":286.28,"unit":"m","source":"Geometría releída del IFC; datum absoluto de proceso provisional","status":"derivado"},{"label":"Cota superior de visualización","value":286.3,"unit":"m","source":"Geometría releída del IFC; datum absoluto de proceso provisional","status":"derivado"}]} | [] | {"Cota inferior relativa (m)":0.18000000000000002,"Cota superior relativa (m)":0.2,"Cero absoluto de visualización (m)":286.1,"Estado del cero absoluto":"Provisional","Criterio":"Las cotas relativas proceden del dibujo; la equivalencia absoluta no está confirmada."} | SUP-C14 | [] | ["C14"] | ZD1 / DZ-1 | ["2CC89","2CD4B","2CDA7","2CC8A","2CC85","2CC86","2CD70","2CEB4","2CE8F"] | SUP-C14/Cimentación de soporte de tuberías C14 · placa embebida MJ-1 | {"boundingBoxM":{"min":[44.754025,59.066508,1.28],"max":[45.204779,59.517262,1.3]},"extentsM":[0.450754,0.450754,0.02],"meshSurfaceM2":0.352,"meshVolumeM3":0.0032,"closedSolid":true,"basis":"Magnitudes de las mallas representadas, no cantidades certificadas de obra, compra o fabricación. Las partes pueden compartir superficies; no se suman como un despiece de materiales."} | {"elementId":"found_0904_0575a6e54392c4","ifcGuid":"3VE4Tl9ePHDfp1ut4vK2N7","ifcClass":"IfcPlate","buildingId":"process_plant","buildingName":"Zona de separación de aire","sourceDocumentId":"LHD2609-JG00100-20260904","sourceRepresentationKind":"foundation"} | 2CC89, 2CD4B, 2CDA7, 2CC8A, 2CC85, 2CC86, 2CD70, 2CEB4, 2CE8F | 0.18 | 0.2 | 0.16 | Contornos y sección documentados por el fabricante | found_0904_0575a6e54392c4 | 0.4 | 0.02 | M1: detalle20 mm; MJ1/MJ2:20 mm derivados del contorno lateral80 mm a escala4, no de una cota explícita. | C14 | Fz=-2000 | 8375.0 / 30700.0
Cimentación de marquesina C15 · placa embebida M1 | 0.507098 | 0.507098 | 0.02 | 286.28 | 286.3 | 0.440999 | 0.00405 | {"documentId":"LHD2609-JG00100-20260904","title":"Cimentaciones de equipos y pedestales del fabricante · revisión recibida 04/09/2026","date":"2026-09-04","sheet":"JC1 / DZ","fileName":"LHD2609-JG00100_20260904.dwg","revisionCaveat":"Fecha de revisión tomada del nombre recibido; cajetines internos mantienen 02/07/2026 y algunos textos de plantilla.","sourceFileSha256":"b42eb027b7bc0b14c38d1d13514f4899b58a732aa8d0ba2ccf10fa2fc3192890"} | {"documented":[{"label":"Extensión local X","value":0.45,"unit":"m","source":"2CC9F, 2CD4C, 2CCBE, 2CD8C, 2CCB0, 2CCB1, 2CD71, 2CEF2, 2CEF1","status":"derivada del contorno CAD"},{"label":"Extensión local Y","value":0.45,"unit":"m","source":"2CC9F, 2CD4C, 2CCBE, 2CD8C, 2CCB0, 2CCB1, 2CD71, 2CEF2, 2CEF1","status":"derivada del contorno CAD"},{"label":"Cota inferior relativa adoptada","value":0.18000000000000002,"unit":"m","source":"JC1 / DZ","status":"documentada"},{"label":"Cota superior relativa adoptada","value":0.2,"unit":"m","source":"JC1 / DZ","status":"documentada / separación por material"}],"geometry":[{"label":"Extensión de la malla en X","value":0.5070979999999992,"unit":"m","source":"Geometría releída del IFC; datum absoluto de proceso provisional","status":"derivado"},{"label":"Extensión de la malla en Y","value":0.5070980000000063,"unit":"m","source":"Geometría releída del IFC; datum absoluto de proceso provisional","status":"derivado"},{"label":"Extensión de la malla en Z","value":0.020000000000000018,"unit":"m","source":"Geometría releída del IFC; datum absoluto de proceso provisional","status":"derivado"},{"label":"Cota inferior de visualización","value":286.28,"unit":"m","source":"Geometría releída del IFC; datum absoluto de proceso provisional","status":"derivado"},{"label":"Cota superior de visualización","value":286.3,"unit":"m","source":"Geometría releída del IFC; datum absoluto de proceso provisional","status":"derivado"}]} | [] | {"Cota inferior relativa (m)":0.18000000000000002,"Cota superior relativa (m)":0.2,"Cero absoluto de visualización (m)":286.1,"Estado del cero absoluto":"Provisional","Criterio":"Las cotas relativas proceden del dibujo; la equivalencia absoluta no está confirmada."} | SUP-C15 | [] | ["C15"] | JC1 / DZ | ["2CC9F","2CD4C","2CCBE","2CD8C","2CCB0","2CCB1","2CD71","2CEF2","2CEF1"] | SUP-C15/Cimentación de marquesina C15 · placa embebida M1 | {"boundingBoxM":{"min":[36.764522,58.215028,1.28],"max":[37.27162,58.722126,1.3]},"extentsM":[0.507098,0.507098,0.02],"meshSurfaceM2":0.440999,"meshVolumeM3":0.00405,"closedSolid":true,"basis":"Magnitudes de las mallas representadas, no cantidades certificadas de obra, compra o fabricación. Las partes pueden compartir superficies; no se suman como un despiece de materiales."} | {"elementId":"found_0904_ae881186e51993","ifcGuid":"2_unVy4FjJsOI8$mBpvaao","ifcClass":"IfcPlate","buildingId":"process_plant","buildingName":"Zona de separación de aire","sourceDocumentId":"LHD2609-JG00100-20260904","sourceRepresentationKind":"foundation"} | 2CC9F, 2CD4C, 2CCBE, 2CD8C, 2CCB0, 2CCB1, 2CD71, 2CEF2, 2CEF1 | 0.18 | 0.2 | 0.2025 | Contornos y sección documentados por el fabricante | found_0904_ae881186e51993 | 0.45 | 0.02 | M1: detalle20 mm; MJ1/MJ2:20 mm derivados del contorno lateral80 mm a escala4, no de una cota explícita. | C15 | / | 600.0 / 28800.0
Cimentación de marquesina C16 · placa embebida M1 | 0.507098 | 0.507098 | 0.02 | 286.28 | 286.3 | 0.441 | 0.00405 | {"documentId":"LHD2609-JG00100-20260904","title":"Cimentaciones de equipos y pedestales del fabricante · revisión recibida 04/09/2026","date":"2026-09-04","sheet":"JC1 / DZ","fileName":"LHD2609-JG00100_20260904.dwg","revisionCaveat":"Fecha de revisión tomada del nombre recibido; cajetines internos mantienen 02/07/2026 y algunos textos de plantilla.","sourceFileSha256":"b42eb027b7bc0b14c38d1d13514f4899b58a732aa8d0ba2ccf10fa2fc3192890"} | {"documented":[{"label":"Extensión local X","value":0.45,"unit":"m","source":"2CCA0, 2CD4D, 2CCBF, 2CD8D, 2CCAE, 2CCAF, 2CD72, 2CEF4, 2CEF3","status":"derivada del contorno CAD"},{"label":"Extensión local Y","value":0.45,"unit":"m","source":"2CCA0, 2CD4D, 2CCBF, 2CD8D, 2CCAE, 2CCAF, 2CD72, 2CEF4, 2CEF3","status":"derivada del contorno CAD"},{"label":"Cota inferior relativa adoptada","value":0.18000000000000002,"unit":"m","source":"JC1 / DZ","status":"documentada"},{"label":"Cota superior relativa adoptada","value":0.2,"unit":"m","source":"JC1 / DZ","status":"documentada / separación por material"}],"geometry":[{"label":"Extensión de la malla en X","value":0.5070979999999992,"unit":"m","source":"Geometría releída del IFC; datum absoluto de proceso provisional","status":"derivado"},{"label":"Extensión de la malla en Y","value":0.5070979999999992,"unit":"m","source":"Geometría releída del IFC; datum absoluto de proceso provisional","status":"derivado"},{"label":"Extensión de la malla en Z","value":0.020000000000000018,"unit":"m","source":"Geometría releída del IFC; datum absoluto de proceso provisional","status":"derivado"},{"label":"Cota inferior de visualización","value":286.28,"unit":"m","source":"Geometría releída del IFC; datum absoluto de proceso provisional","status":"derivado"},{"label":"Cota superior de visualización","value":286.3,"unit":"m","source":"Geometría releída del IFC; datum absoluto de proceso provisional","status":"derivado"}]} | [] | {"Cota inferior relativa (m)":0.18000000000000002,"Cota superior relativa (m)":0.2,"Cero absoluto de visualización (m)":286.1,"Estado del cero absoluto":"Provisional","Criterio":"Las cotas relativas proceden del dibujo; la equivalencia absoluta no está confirmada."} | SUP-C16 | [] | ["C16"] | JC1 / DZ | ["2CCA0","2CD4D","2CCBF","2CD8D","2CCAE","2CCAF","2CD72","2CEF4","2CEF3"] | SUP-C16/Cimentación de marquesina C16 · placa embebida M1 | {"boundingBoxM":{"min":[36.410392,55.639258,1.28],"max":[36.91749,56.146356,1.3]},"extentsM":[0.507098,0.507098,0.02],"meshSurfaceM2":0.441,"meshVolumeM3":0.00405,"closedSolid":true,"basis":"Magnitudes de las mallas representadas, no cantidades certificadas de obra, compra o fabricación. Las partes pueden compartir superficies; no se suman como un despiece de materiales."} | {"elementId":"found_0904_55f09d36ed16f4","ifcGuid":"2IcOyGrI9GfxbHAkhOyycy","ifcClass":"IfcPlate","buildingId":"process_plant","buildingName":"Zona de separación de aire","sourceDocumentId":"LHD2609-JG00100-20260904","sourceRepresentationKind":"foundation"} | 2CCA0, 2CD4D, 2CCBF, 2CD8D, 2CCAE, 2CCAF, 2CD72, 2CEF4, 2CEF3 | 0.18 | 0.2 | 0.2025 | Contornos y sección documentados por el fabricante | found_0904_55f09d36ed16f4 | 0.45 | 0.02 | M1: detalle20 mm; MJ1/MJ2:20 mm derivados del contorno lateral80 mm a escala4, no de una cota explícita. | C16 | / | 600.0 / 26200.0
Cimentación de marquesina C17 · placa embebida M1 | 0.507098 | 0.507098 | 0.02 | 286.28 | 286.3 | 0.441 | 0.00405 | {"documentId":"LHD2609-JG00100-20260904","title":"Cimentaciones de equipos y pedestales del fabricante · revisión recibida 04/09/2026","date":"2026-09-04","sheet":"JC1 / DZ","fileName":"LHD2609-JG00100_20260904.dwg","revisionCaveat":"Fecha de revisión tomada del nombre recibido; cajetines internos mantienen 02/07/2026 y algunos textos de plantilla.","sourceFileSha256":"b42eb027b7bc0b14c38d1d13514f4899b58a732aa8d0ba2ccf10fa2fc3192890"} | {"documented":[{"label":"Extensión local X","value":0.45,"unit":"m","source":"2CCA1, 2CD4E, 2CCC0, 2CD8E, 2CCAB, 2CCAC, 2CD73, 2CEF6, 2CEF5","status":"derivada del contorno CAD"},{"label":"Extensión local Y","value":0.45,"unit":"m","source":"2CCA1, 2CD4E, 2CCC0, 2CD8E, 2CCAB, 2CCAC, 2CD73, 2CEF6, 2CEF5","status":"derivada del contorno CAD"},{"label":"Cota inferior relativa adoptada","value":0.18000000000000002,"unit":"m","source":"JC1 / DZ","status":"documentada"},{"label":"Cota superior relativa adoptada","value":0.2,"unit":"m","source":"JC1 / DZ","status":"documentada / separación por material"}],"geometry":[{"label":"Extensión de la malla en X","value":0.5070980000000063,"unit":"m","source":"Geometría releída del IFC; datum absoluto de proceso provisional","status":"derivado"},{"label":"Extensión de la malla en Y","value":0.5070979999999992,"unit":"m","source":"Geometría releída del IFC; datum absoluto de proceso provisional","status":"derivado"},{"label":"Extensión de la malla en Z","value":0.020000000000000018,"unit":"m","source":"Geometría releída del IFC; datum absoluto de proceso provisional","status":"derivado"},{"label":"Cota inferior de visualización","value":286.28,"unit":"m","source":"Geometría releída del IFC; datum absoluto de proceso provisional","status":"derivado"},{"label":"Cota superior de visualización","value":286.3,"unit":"m","source":"Geometría releída del IFC; datum absoluto de proceso provisional","status":"derivado"}]} | [] | {"Cota inferior relativa (m)":0.18000000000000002,"Cota superior relativa (m)":0.2,"Cero absoluto de visualización (m)":286.1,"Estado del cero absoluto":"Provisional","Criterio":"Las cotas relativas proceden del dibujo; la equivalencia absoluta no está confirmada."} | SUP-C17 | [] | ["C17"] | JC1 / DZ | ["2CCA1","2CD4E","2CCC0","2CD8E","2CCAB","2CCAC","2CD73","2CEF6","2CEF5"] | SUP-C17/Cimentación de marquesina C17 · placa embebida M1 | {"boundingBoxM":{"min":[42.560005,57.418235,1.28],"max":[43.067103,57.925333,1.3]},"extentsM":[0.507098,0.507098,0.02],"meshSurfaceM2":0.441,"meshVolumeM3":0.00405,"closedSolid":true,"basis":"Magnitudes de las mallas representadas, no cantidades certificadas de obra, compra o fabricación. Las partes pueden compartir superficies; no se suman como un despiece de materiales."} | {"elementId":"found_0904_b69e106f03a2c9","ifcGuid":"0slTATQbLVH9yutR1RO2e1","ifcClass":"IfcPlate","buildingId":"process_plant","buildingName":"Zona de separación de aire","sourceDocumentId":"LHD2609-JG00100-20260904","sourceRepresentationKind":"foundation"} | 2CCA1, 2CD4E, 2CCC0, 2CD8E, 2CCAB, 2CCAC, 2CD73, 2CEF6, 2CEF5 | 0.18 | 0.2 | 0.2025 | Contornos y sección documentados por el fabricante | found_0904_b69e106f03a2c9 | 0.45 | 0.02 | M1: detalle20 mm; MJ1/MJ2:20 mm derivados del contorno lateral80 mm a escala4, no de una cota explícita. | C17 | / | 6450.0 / 28800.0
Cimentación de marquesina C18 · placa embebida M1 | 0.507099 | 0.507098 | 0.02 | 286.28 | 286.3 | 0.441001 | 0.00405 | {"documentId":"LHD2609-JG00100-20260904","title":"Cimentaciones de equipos y pedestales del fabricante · revisión recibida 04/09/2026","date":"2026-09-04","sheet":"JC1 / DZ","fileName":"LHD2609-JG00100_20260904.dwg","revisionCaveat":"Fecha de revisión tomada del nombre recibido; cajetines internos mantienen 02/07/2026 y algunos textos de plantilla.","sourceFileSha256":"b42eb027b7bc0b14c38d1d13514f4899b58a732aa8d0ba2ccf10fa2fc3192890"} | {"documented":[{"label":"Extensión local X","value":0.45,"unit":"m","source":"2CCA2, 2CD4F, 2CCC1, 2CD8F, 2CCAA, 2CCAD, 2CD74, 2CEF8, 2CEF7","status":"derivada del contorno CAD"},{"label":"Extensión local Y","value":0.45,"unit":"m","source":"2CCA2, 2CD4F, 2CCC1, 2CD8F, 2CCAA, 2CCAD, 2CD74, 2CEF8, 2CEF7","status":"derivada del contorno CAD"},{"label":"Cota inferior relativa adoptada","value":0.18000000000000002,"unit":"m","source":"JC1 / DZ","status":"documentada"},{"label":"Cota superior relativa adoptada","value":0.2,"unit":"m","source":"JC1 / DZ","status":"documentada / separación por material"}],"geometry":[{"label":"Extensión de la malla en X","value":0.5070989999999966,"unit":"m","source":"Geometría releída del IFC; datum absoluto de proceso provisional","status":"derivado"},{"label":"Extensión de la malla en Y","value":0.5070980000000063,"unit":"m","source":"Geometría releída del IFC; datum absoluto de proceso provisional","status":"derivado"},{"label":"Extensión de la malla en Z","value":0.020000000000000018,"unit":"m","source":"Geometría releída del IFC; datum absoluto de proceso provisional","status":"derivado"},{"label":"Cota inferior de visualización","value":286.28,"unit":"m","source":"Geometría releída del IFC; datum absoluto de proceso provisional","status":"derivado"},{"label":"Cota superior de visualización","value":286.3,"unit":"m","source":"Geometría releída del IFC; datum absoluto de proceso provisional","status":"derivado"}]} | [] | {"Cota inferior relativa (m)":0.18000000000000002,"Cota superior relativa (m)":0.2,"Cero absoluto de visualización (m)":286.1,"Estado del cero absoluto":"Provisional","Criterio":"Las cotas relativas proceden del dibujo; la equivalencia absoluta no está confirmada."} | SUP-C18 | [] | ["C18"] | JC1 / DZ | ["2CCA2","2CD4F","2CCC1","2CD8F","2CCAA","2CCAD","2CD74","2CEF8","2CEF7"] | SUP-C18/Cimentación de marquesina C18 · placa embebida M1 | {"boundingBoxM":{"min":[42.205874,54.842465,1.28],"max":[42.712973,55.349563,1.3]},"extentsM":[0.507099,0.507098,0.02],"meshSurfaceM2":0.441001,"meshVolumeM3":0.00405,"closedSolid":true,"basis":"Magnitudes de las mallas representadas, no cantidades certificadas de obra, compra o fabricación. Las partes pueden compartir superficies; no se suman como un despiece de materiales."} | {"elementId":"found_0904_d1c8d8edf50b27","ifcGuid":"30Sc$mVEzROQocQw4WGtLL","ifcClass":"IfcPlate","buildingId":"process_plant","buildingName":"Zona de separación de aire","sourceDocumentId":"LHD2609-JG00100-20260904","sourceRepresentationKind":"foundation"} | 2CCA2, 2CD4F, 2CCC1, 2CD8F, 2CCAA, 2CCAD, 2CD74, 2CEF8, 2CEF7 | 0.18 | 0.2 | 0.2025 | Contornos y sección documentados por el fabricante | found_0904_d1c8d8edf50b27 | 0.45 | 0.02 | M1: detalle20 mm; MJ1/MJ2:20 mm derivados del contorno lateral80 mm a escala4, no de una cota explícita. | C18 | / | 6450.0 / 26200.0
Cimentación de soporte de tuberías C19 · placa embebida MJ-1 | 0.450754 | 0.450754 | 0.02 | 286.28 | 286.3 | 0.352 | 0.0032 | {"documentId":"LHD2609-JG00100-20260904","title":"Cimentaciones de equipos y pedestales del fabricante · revisión recibida 04/09/2026","date":"2026-09-04","sheet":"ZD1 / DZ-1","fileName":"LHD2609-JG00100_20260904.dwg","revisionCaveat":"Fecha de revisión tomada del nombre recibido; cajetines internos mantienen 02/07/2026 y algunos textos de plantilla.","sourceFileSha256":"b42eb027b7bc0b14c38d1d13514f4899b58a732aa8d0ba2ccf10fa2fc3192890"} | {"documented":[{"label":"Extensión local X","value":0.4,"unit":"m","source":"2CCA3, 2CD50, 2CCC2, 2CD90, 2CCB2, 2CCB4, 2CD75, 2CEB5, 2CE90","status":"derivada del contorno CAD"},{"label":"Extensión local Y","value":0.4,"unit":"m","source":"2CCA3, 2CD50, 2CCC2, 2CD90, 2CCB2, 2CCB4, 2CD75, 2CEB5, 2CE90","status":"derivada del contorno CAD"},{"label":"Cota inferior relativa adoptada","value":0.18000000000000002,"unit":"m","source":"ZD1 / DZ-1","status":"documentada"},{"label":"Cota superior relativa adoptada","value":0.2,"unit":"m","source":"ZD1 / DZ-1","status":"documentada / separación por material"}],"geometry":[{"label":"Extensión de la malla en X","value":0.4507539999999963,"unit":"m","source":"Geometría releída del IFC; datum absoluto de proceso provisional","status":"derivado"},{"label":"Extensión de la malla en Y","value":0.45075400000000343,"unit":"m","source":"Geometría releída del IFC; datum absoluto de proceso provisional","status":"derivado"},{"label":"Extensión de la malla en Z","value":0.020000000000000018,"unit":"m","source":"Geometría releída del IFC; datum absoluto de proceso provisional","status":"derivado"},{"label":"Cota inferior de visualización","value":286.28,"unit":"m","source":"Geometría releída del IFC; datum absoluto de proceso provisional","status":"derivado"},{"label":"Cota superior de visualización","value":286.3,"unit":"m","source":"Geometría releída del IFC; datum absoluto de proceso provisional","status":"derivado"}]} | [] | {"Cota inferior relativa (m)":0.18000000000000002,"Cota superior relativa (m)":0.2,"Cero absoluto de visualización (m)":286.1,"Estado del cero absoluto":"Provisional","Criterio":"Las cotas relativas proceden del dibujo; la equivalencia absoluta no está confirmada."} | SUP-C19 | [] | ["C19"] | ZD1 / DZ-1 | ["2CCA3","2CD50","2CCC2","2CD90","2CCB2","2CCB4","2CD75","2CEB5","2CE90"] | SUP-C19/Cimentación de soporte de tuberías C19 · placa embebida MJ-1 | {"boundingBoxM":{"min":[42.933722,54.269738,1.28],"max":[43.384476,54.720492,1.3]},"extentsM":[0.450754,0.450754,0.02],"meshSurfaceM2":0.352,"meshVolumeM3":0.0032,"closedSolid":true,"basis":"Magnitudes de las mallas representadas, no cantidades certificadas de obra, compra o fabricación. Las partes pueden compartir superficies; no se suman como un despiece de materiales."} | {"elementId":"found_0904_3f34928469b42d","ifcGuid":"2eOa3MdRbOLRTuzYmY4xa8","ifcClass":"IfcPlate","buildingId":"process_plant","buildingName":"Zona de separación de aire","sourceDocumentId":"LHD2609-JG00100-20260904","sourceRepresentationKind":"foundation"} | 2CCA3, 2CD50, 2CCC2, 2CD90, 2CCB2, 2CCB4, 2CD75, 2CEB5, 2CE90 | 0.18 | 0.2 | 0.16 | Contornos y sección documentados por el fabricante | found_0904_3f34928469b42d | 0.4 | 0.02 | M1: detalle20 mm; MJ1/MJ2:20 mm derivados del contorno lateral80 mm a escala4, no de una cota explícita. | C19 | Fz=-2000 | 7225.0 / 25700.0
Cimentación de soporte de tuberías C20 · placa embebida MJ-1 | 0.450754 | 0.450754 | 0.02 | 286.28 | 286.3 | 0.352 | 0.0032 | {"documentId":"LHD2609-JG00100-20260904","title":"Cimentaciones de equipos y pedestales del fabricante · revisión recibida 04/09/2026","date":"2026-09-04","sheet":"ZD1 / DZ-1","fileName":"LHD2609-JG00100_20260904.dwg","revisionCaveat":"Fecha de revisión tomada del nombre recibido; cajetines internos mantienen 02/07/2026 y algunos textos de plantilla.","sourceFileSha256":"b42eb027b7bc0b14c38d1d13514f4899b58a732aa8d0ba2ccf10fa2fc3192890"} | {"documented":[{"label":"Extensión local X","value":0.4,"unit":"m","source":"2CCA4, 2CD51, 2CCC3, 2CD91, 2CCB3, 2CCB5, 2CD76, 2CEB6, 2CE91","status":"derivada del contorno CAD"},{"label":"Extensión local Y","value":0.4,"unit":"m","source":"2CCA4, 2CD51, 2CCC3, 2CD91, 2CCB3, 2CCB5, 2CD76, 2CEB6, 2CE91","status":"derivada del contorno CAD"},{"label":"Cota inferior relativa adoptada","value":0.18000000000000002,"unit":"m","source":"ZD1 / DZ-1","status":"interpretación con conflicto conservado"},{"label":"Cota superior relativa adoptada","value":0.2,"unit":"m","source":"ZD1 / DZ-1","status":"documentada / separación por material"}],"geometry":[{"label":"Extensión de la malla en X","value":0.4507539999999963,"unit":"m","source":"Geometría releída del IFC; datum absoluto de proceso provisional","status":"derivado"},{"label":"Extensión de la malla en Y","value":0.45075400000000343,"unit":"m","source":"Geometría releída del IFC; datum absoluto de proceso provisional","status":"derivado"},{"label":"Extensión de la malla en Z","value":0.020000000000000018,"unit":"m","source":"Geometría releída del IFC; datum absoluto de proceso provisional","status":"derivado"},{"label":"Cota inferior de visualización","value":286.28,"unit":"m","source":"Geometría releída del IFC; datum absoluto de proceso provisional","status":"derivado"},{"label":"Cota superior de visualización","value":286.3,"unit":"m","source":"Geometría releída del IFC; datum absoluto de proceso provisional","status":"derivado"}]} | ["Identificador original HA-20 en columna de posición; C20 se infiere por secuencia. Se conserva el original y no se interpreta como material."] | {"Cota inferior relativa (m)":0.18000000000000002,"Cota superior relativa (m)":0.2,"Cero absoluto de visualización (m)":286.1,"Estado del cero absoluto":"Provisional","Criterio":"Las cotas relativas proceden del dibujo; la equivalencia absoluta no está confirmada."} | SUP-C20 | [] | ["C20"] | ZD1 / DZ-1 | ["2CCA4","2CD51","2CCC3","2CD91","2CCB3","2CCB5","2CD76","2CEB6","2CE91"] | SUP-C20/Cimentación de soporte de tuberías C20 · placa embebida MJ-1 | {"boundingBoxM":{"min":[44.073005,54.113104,1.28],"max":[44.523759,54.563858,1.3]},"extentsM":[0.450754,0.450754,0.02],"meshSurfaceM2":0.352,"meshVolumeM3":0.0032,"closedSolid":true,"basis":"Magnitudes de las mallas representadas, no cantidades certificadas de obra, compra o fabricación. Las partes pueden compartir superficies; no se suman como un despiece de materiales."} | {"elementId":"found_0904_6bd758803db21c","ifcGuid":"2mHH5vnVjUdf$93o32T$kB","ifcClass":"IfcPlate","buildingId":"process_plant","buildingName":"Zona de separación de aire","sourceDocumentId":"LHD2609-JG00100-20260904","sourceRepresentationKind":"foundation"} | 2CCA4, 2CD51, 2CCC3, 2CD91, 2CCB3, 2CCB5, 2CD76, 2CEB6, 2CE91 | 0.18 | 0.2 | 0.16 | Sección y contornos del fabricante; incidencias conservadas | found_0904_6bd758803db21c | 0.4 | 0.02 | M1: detalle20 mm; MJ1/MJ2:20 mm derivados del contorno lateral80 mm a escala4, no de una cota explícita. | HA-20 | Fz=-2000 | 8375.0 / 25700.0 | JH_Trazabilidad - Incidencias de origen: Identificador original HA-20 en columna de posición; C20 se infiere por secuencia. Se conserva el original y no se interpreta como material.
Cimentación de soporte de tuberías C21 · placa embebida MJ-2 | 0.507099 | 0.507099 | 0.02 | 286.18 | 286.2 | 0.441001 | 0.00405 | {"documentId":"LHD2609-JG00100-20260904","title":"Cimentaciones de equipos y pedestales del fabricante · revisión recibida 04/09/2026","date":"2026-09-04","sheet":"ZD1 / DZ-2","fileName":"LHD2609-JG00100_20260904.dwg","revisionCaveat":"Fecha de revisión tomada del nombre recibido; cajetines internos mantienen 02/07/2026 y algunos textos de plantilla.","sourceFileSha256":"b42eb027b7bc0b14c38d1d13514f4899b58a732aa8d0ba2ccf10fa2fc3192890"} | {"documented":[{"label":"Extensión local X","value":0.45,"unit":"m","source":"2CCA5, 2CD52, 2CCC4, 2CD92, 2CCBD, 2CCB8, 2CD77, 2CEB7, 2CE92","status":"derivada del contorno CAD"},{"label":"Extensión local Y","value":0.45,"unit":"m","source":"2CCA5, 2CD52, 2CCC4, 2CD92, 2CCBD, 2CCB8, 2CD77, 2CEB7, 2CE92","status":"derivada del contorno CAD"},{"label":"Cota inferior relativa adoptada","value":0.08,"unit":"m","source":"ZD1 / DZ-2","status":"documentada"},{"label":"Cota superior relativa adoptada","value":0.1,"unit":"m","source":"ZD1 / DZ-2","status":"documentada / separación por material"}],"geometry":[{"label":"Extensión de la malla en X","value":0.5070989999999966,"unit":"m","source":"Geometría releída del IFC; datum absoluto de proceso provisional","status":"derivado"},{"label":"Extensión de la malla en Y","value":0.5070990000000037,"unit":"m","source":"Geometría releída del IFC; datum absoluto de proceso provisional","status":"derivado"},{"label":"Extensión de la malla en Z","value":0.020000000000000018,"unit":"m","source":"Geometría releída del IFC; datum absoluto de proceso provisional","status":"derivado"},{"label":"Cota inferior de visualización","value":286.18,"unit":"m","source":"Geometría releída del IFC; datum absoluto de proceso provisional","status":"derivado"},{"label":"Cota superior de visualización","value":286.2,"unit":"m","source":"Geometría releída del IFC; datum absoluto de proceso provisional","status":"derivado"}]} | [] | {"Cota inferior relativa (m)":0.08,"Cota superior relativa (m)":0.1,"Cero absoluto de visualización (m)":286.1,"Estado del cero absoluto":"Provisional","Criterio":"Las cotas relativas proceden del dibujo; la equivalencia absoluta no está confirmada."} | SUP-C21 | [] | ["C21"] | ZD1 / DZ-2 | ["2CCA5","2CD52","2CCC4","2CD92","2CCBD","2CCB8","2CD77","2CEB7","2CE92"] | SUP-C21/Cimentación de soporte de tuberías C21 · placa embebida MJ-2 | {"boundingBoxM":{"min":[51.707737,53.838921,1.18],"max":[52.214836,54.34602,1.2]},"extentsM":[0.507099,0.507099,0.02],"meshSurfaceM2":0.441001,"meshVolumeM3":0.00405,"closedSolid":true,"basis":"Magnitudes de las mallas representadas, no cantidades certificadas de obra, compra o fabricación. Las partes pueden compartir superficies; no se suman como un despiece de materiales."} | {"elementId":"found_0904_f26f03ffc09b6b","ifcGuid":"1HTRw1UxDMWx5Px0R2_uNZ","ifcClass":"IfcPlate","buildingId":"process_plant","buildingName":"Zona de separación de aire","sourceDocumentId":"LHD2609-JG00100-20260904","sourceRepresentationKind":"foundation"} | 2CCA5, 2CD52, 2CCC4, 2CD92, 2CCBD, 2CCB8, 2CD77, 2CEB7, 2CE92 | 0.08 | 0.1 | 0.2025 | Contornos y sección documentados por el fabricante | found_0904_f26f03ffc09b6b | 0.45 | 0.02 | M1: detalle20 mm; MJ1/MJ2:20 mm derivados del contorno lateral80 mm a escala4, no de una cota explícita. | C21 | Fz=-2500 | 16000.0 / 26500.0
Cimentación de soporte de tuberías C22 · placa embebida MJ-2 | 0.507098 | 0.507098 | 0.02 | 286.18 | 286.2 | 0.441 | 0.00405 | {"documentId":"LHD2609-JG00100-20260904","title":"Cimentaciones de equipos y pedestales del fabricante · revisión recibida 04/09/2026","date":"2026-09-04","sheet":"ZD1 / DZ-2","fileName":"LHD2609-JG00100_20260904.dwg","revisionCaveat":"Fecha de revisión tomada del nombre recibido; cajetines internos mantienen 02/07/2026 y algunos textos de plantilla.","sourceFileSha256":"b42eb027b7bc0b14c38d1d13514f4899b58a732aa8d0ba2ccf10fa2fc3192890"} | {"documented":[{"label":"Extensión local X","value":0.45,"unit":"m","source":"2CCA6, 2CD53, 2CCC5, 2CD93, 2CCBB, 2CCBC, 2CD82, 2CEB8, 2CE93","status":"derivada del contorno CAD"},{"label":"Extensión local Y","value":0.45,"unit":"m","source":"2CCA6, 2CD53, 2CCC5, 2CD93, 2CCBB, 2CCBC, 2CD82, 2CEB8, 2CE93","status":"derivada del contorno CAD"},{"label":"Cota inferior relativa adoptada","value":0.08,"unit":"m","source":"ZD1 / DZ-2","status":"documentada"},{"label":"Cota superior relativa adoptada","value":0.1,"unit":"m","source":"ZD1 / DZ-2","status":"documentada / separación por material"}],"geometry":[{"label":"Extensión de la malla en X","value":0.5070979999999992,"unit":"m","source":"Geometría releída del IFC; datum absoluto de proceso provisional","status":"derivado"},{"label":"Extensión de la malla en Y","value":0.5070979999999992,"unit":"m","source":"Geometría releída del IFC; datum absoluto de proceso provisional","status":"derivado"},{"label":"Extensión de la malla en Z","value":0.020000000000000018,"unit":"m","source":"Geometría releída del IFC; datum absoluto de proceso provisional","status":"derivado"},{"label":"Cota inferior de visualización","value":286.18,"unit":"m","source":"Geometría releída del IFC; datum absoluto de proceso provisional","status":"derivado"},{"label":"Cota superior de visualización","value":286.2,"unit":"m","source":"Geometría releída del IFC; datum absoluto de proceso provisional","status":"derivado"}]} | [] | {"Cota inferior relativa (m)":0.08,"Cota superior relativa (m)":0.1,"Cero absoluto de visualización (m)":286.1,"Estado del cero absoluto":"Provisional","Criterio":"Las cotas relativas proceden del dibujo; la equivalencia absoluta no está confirmada."} | SUP-C22 | [] | ["C22"] | ZD1 / DZ-2 | ["2CCA6","2CD53","2CCC5","2CD93","2CCBB","2CCBC","2CD82","2CEB8","2CE93"] | SUP-C22/Cimentación de soporte de tuberías C22 · placa embebida MJ-2 | {"boundingBoxM":{"min":[54.333042,53.477981,1.18],"max":[54.84014,53.985079,1.2]},"extentsM":[0.507098,0.507098,0.02],"meshSurfaceM2":0.441,"meshVolumeM3":0.00405,"closedSolid":true,"basis":"Magnitudes de las mallas representadas, no cantidades certificadas de obra, compra o fabricación. Las partes pueden compartir superficies; no se suman como un despiece de materiales."} | {"elementId":"found_0904_114eeb636c157b","ifcGuid":"26BFYZNYLRiAvF6YGlPjFs","ifcClass":"IfcPlate","buildingId":"process_plant","buildingName":"Zona de separación de aire","sourceDocumentId":"LHD2609-JG00100-20260904","sourceRepresentationKind":"foundation"} | 2CCA6, 2CD53, 2CCC5, 2CD93, 2CCBB, 2CCBC, 2CD82, 2CEB8, 2CE93 | 0.08 | 0.1 | 0.2025 | Contornos y sección documentados por el fabricante | found_0904_114eeb636c157b | 0.45 | 0.02 | M1: detalle20 mm; MJ1/MJ2:20 mm derivados del contorno lateral80 mm a escala4, no de una cota explícita. | C22 | Fz=-2500 | 18650.0 / 26500.0
Cimentación de soporte de tuberías C23 · placa embebida MJ-2 | 0.507098 | 0.507098 | 0.02 | 286.28 | 286.3 | 0.441 | 0.00405 | {"documentId":"LHD2609-JG00100-20260904","title":"Cimentaciones de equipos y pedestales del fabricante · revisión recibida 04/09/2026","date":"2026-09-04","sheet":"ZD1 / DZ-2","fileName":"LHD2609-JG00100_20260904.dwg","revisionCaveat":"Fecha de revisión tomada del nombre recibido; cajetines internos mantienen 02/07/2026 y algunos textos de plantilla.","sourceFileSha256":"b42eb027b7bc0b14c38d1d13514f4899b58a732aa8d0ba2ccf10fa2fc3192890"} | {"documented":[{"label":"Extensión local X","value":0.45,"unit":"m","source":"2CCA7, 2CD5F, 2CCC6, 2CD94, 2CCB9, 2CCBA, 2CD83, 2CEB9, 2CE94","status":"derivada del contorno CAD"},{"label":"Extensión local Y","value":0.45,"unit":"m","source":"2CCA7, 2CD5F, 2CCC6, 2CD94, 2CCB9, 2CCBA, 2CD83, 2CEB9, 2CE94","status":"derivada del contorno CAD"},{"label":"Cota inferior relativa adoptada","value":0.18000000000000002,"unit":"m","source":"ZD1 / DZ-2","status":"documentada"},{"label":"Cota superior relativa adoptada","value":0.2,"unit":"m","source":"ZD1 / DZ-2","status":"documentada / separación por material"}],"geometry":[{"label":"Extensión de la malla en X","value":0.5070979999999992,"unit":"m","source":"Geometría releída del IFC; datum absoluto de proceso provisional","status":"derivado"},{"label":"Extensión de la malla en Y","value":0.5070979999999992,"unit":"m","source":"Geometría releída del IFC; datum absoluto de proceso provisional","status":"derivado"},{"label":"Extensión de la malla en Z","value":0.020000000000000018,"unit":"m","source":"Geometría releída del IFC; datum absoluto de proceso provisional","status":"derivado"},{"label":"Cota inferior de visualización","value":286.28,"unit":"m","source":"Geometría releída del IFC; datum absoluto de proceso provisional","status":"derivado"},{"label":"Cota superior de visualización","value":286.3,"unit":"m","source":"Geometría releída del IFC; datum absoluto de proceso provisional","status":"derivado"}]} | [] | {"Cota inferior relativa (m)":0.18000000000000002,"Cota superior relativa (m)":0.2,"Cero absoluto de visualización (m)":286.1,"Estado del cero absoluto":"Provisional","Criterio":"Las cotas relativas proceden del dibujo; la equivalencia absoluta no está confirmada."} | SUP-C23 | [] | ["C23"] | ZD1 / DZ-2 | ["2CCA7","2CD5F","2CCC6","2CD94","2CCB9","2CCBA","2CD83","2CEB9","2CE94"] | SUP-C23/Cimentación de soporte de tuberías C23 · placa embebida MJ-2 | {"boundingBoxM":{"min":[56.642574,52.655751,1.28],"max":[57.149672,53.162849,1.3]},"extentsM":[0.507098,0.507098,0.02],"meshSurfaceM2":0.441,"meshVolumeM3":0.00405,"closedSolid":true,"basis":"Magnitudes de las mallas representadas, no cantidades certificadas de obra, compra o fabricación. Las partes pueden compartir superficies; no se suman como un despiece de materiales."} | {"elementId":"found_0904_fbd58bca8dd92b","ifcGuid":"3WumBd9MzLLhsz6Cr3Ry3a","ifcClass":"IfcPlate","buildingId":"process_plant","buildingName":"Zona de separación de aire","sourceDocumentId":"LHD2609-JG00100-20260904","sourceRepresentationKind":"foundation"} | 2CCA7, 2CD5F, 2CCC6, 2CD94, 2CCB9, 2CCBA, 2CD83, 2CEB9, 2CE94 | 0.18 | 0.2 | 0.2025 | Contornos y sección documentados por el fabricante | found_0904_fbd58bca8dd92b | 0.45 | 0.02 | M1: detalle20 mm; MJ1/MJ2:20 mm derivados del contorno lateral80 mm a escala4, no de una cota explícita. | C23 | Fz=-1500 | 21050.0 / 26000.0
Cimentación de soporte de tuberías C24 · placa embebida MJ-2 | 0.507098 | 0.507098 | 0.02 | 286.28 | 286.3 | 0.440999 | 0.00405 | {"documentId":"LHD2609-JG00100-20260904","title":"Cimentaciones de equipos y pedestales del fabricante · revisión recibida 04/09/2026","date":"2026-09-04","sheet":"ZD1 / DZ-2","fileName":"LHD2609-JG00100_20260904.dwg","revisionCaveat":"Fecha de revisión tomada del nombre recibido; cajetines internos mantienen 02/07/2026 y algunos textos de plantilla.","sourceFileSha256":"b42eb027b7bc0b14c38d1d13514f4899b58a732aa8d0ba2ccf10fa2fc3192890"} | {"documented":[{"label":"Extensión local X","value":0.45,"unit":"m","source":"2CCA8, 2CD60, 2CCC7, 2CD95, 2CCB6, 2CCB7, 2CD84, 2CEBA, 2CE95","status":"derivada del contorno CAD"},{"label":"Extensión local Y","value":0.45,"unit":"m","source":"2CCA8, 2CD60, 2CCC7, 2CD95, 2CCB6, 2CCB7, 2CD84, 2CEBA, 2CE95","status":"derivada del contorno CAD"},{"label":"Cota inferior relativa adoptada","value":0.18000000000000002,"unit":"m","source":"ZD1 / DZ-2","status":"documentada"},{"label":"Cota superior relativa adoptada","value":0.2,"unit":"m","source":"ZD1 / DZ-2","status":"documentada / separación por material"}],"geometry":[{"label":"Extensión de la malla en X","value":0.5070979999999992,"unit":"m","source":"Geometría releída del IFC; datum absoluto de proceso provisional","status":"derivado"},{"label":"Extensión de la malla en Y","value":0.5070979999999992,"unit":"m","source":"Geometría releída del IFC; datum absoluto de proceso provisional","status":"derivado"},{"label":"Extensión de la malla en Z","value":0.020000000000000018,"unit":"m","source":"Geometría releída del IFC; datum absoluto de proceso provisional","status":"derivado"},{"label":"Cota inferior de visualización","value":286.28,"unit":"m","source":"Geometría releída del IFC; datum absoluto de proceso provisional","status":"derivado"},{"label":"Cota superior de visualización","value":286.3,"unit":"m","source":"Geometría releída del IFC; datum absoluto de proceso provisional","status":"derivado"}]} | [] | {"Cota inferior relativa (m)":0.18000000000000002,"Cota superior relativa (m)":0.2,"Cero absoluto de visualización (m)":286.1,"Estado del cero absoluto":"Provisional","Criterio":"Las cotas relativas proceden del dibujo; la equivalencia absoluta no está confirmada."} | SUP-C24 | [] | ["C24"] | ZD1 / DZ-2 | ["2CCA8","2CD60","2CCC7","2CD95","2CCB6","2CCB7","2CD84","2CEBA","2CE95"] | SUP-C24/Cimentación de soporte de tuberías C24 · placa embebida MJ-2 | {"boundingBoxM":{"min":[56.438268,51.16973,1.28],"max":[56.945366,51.676828,1.3]},"extentsM":[0.507098,0.507098,0.02],"meshSurfaceM2":0.440999,"meshVolumeM3":0.00405,"closedSolid":true,"basis":"Magnitudes de las mallas representadas, no cantidades certificadas de obra, compra o fabricación. Las partes pueden compartir superficies; no se suman como un despiece de materiales."} | {"elementId":"found_0904_5eaf96f8a50d48","ifcGuid":"3zMiVpoDbObefVkEg7mYwS","ifcClass":"IfcPlate","buildingId":"process_plant","buildingName":"Zona de separación de aire","sourceDocumentId":"LHD2609-JG00100-20260904","sourceRepresentationKind":"foundation"} | 2CCA8, 2CD60, 2CCC7, 2CD95, 2CCB6, 2CCB7, 2CD84, 2CEBA, 2CE95 | 0.18 | 0.2 | 0.2025 | Contornos y sección documentados por el fabricante | found_0904_5eaf96f8a50d48 | 0.45 | 0.02 | M1: detalle20 mm; MJ1/MJ2:20 mm derivados del contorno lateral80 mm a escala4, no de una cota explícita. | C24 | Fz=-1500 | 21050.0 / 24500.0
Cimentación de soporte de tuberías C25 · placa embebida MJ-1 | 0.450754 | 0.450754 | 0.02 | 286.28 | 286.3 | 0.352 | 0.0032 | {"documentId":"LHD2609-JG00100-20260904","title":"Cimentaciones de equipos y pedestales del fabricante · revisión recibida 04/09/2026","date":"2026-09-04","sheet":"ZD1 / DZ-1","fileName":"LHD2609-JG00100_20260904.dwg","revisionCaveat":"Fecha de revisión tomada del nombre recibido; cajetines internos mantienen 02/07/2026 y algunos textos de plantilla.","sourceFileSha256":"b42eb027b7bc0b14c38d1d13514f4899b58a732aa8d0ba2ccf10fa2fc3192890"} | {"documented":[{"label":"Extensión local X","value":0.4,"unit":"m","source":"2CCDA, 2CD54, 2CCF2, 2CD96, 2CCE3, 2CCE4, 2CD78, 2CEBB, 2CE96","status":"derivada del contorno CAD"},{"label":"Extensión local Y","value":0.4,"unit":"m","source":"2CCDA, 2CD54, 2CCF2, 2CD96, 2CCE3, 2CCE4, 2CD78, 2CEBB, 2CE96","status":"derivada del contorno CAD"},{"label":"Cota inferior relativa adoptada","value":0.18000000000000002,"unit":"m","source":"ZD1 / DZ-1","status":"documentada"},{"label":"Cota superior relativa adoptada","value":0.2,"unit":"m","source":"ZD1 / DZ-1","status":"documentada / separación por material"}],"geometry":[{"label":"Extensión de la malla en X","value":0.4507539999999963,"unit":"m","source":"Geometría releída del IFC; datum absoluto de proceso provisional","status":"derivado"},{"label":"Extensión de la malla en Y","value":0.4507539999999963,"unit":"m","source":"Geometría releída del IFC; datum absoluto de proceso provisional","status":"derivado"},{"label":"Extensión de la malla en Z","value":0.020000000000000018,"unit":"m","source":"Geometría releída del IFC; datum absoluto de proceso provisional","status":"derivado"},{"label":"Cota inferior de visualización","value":286.28,"unit":"m","source":"Geometría releída del IFC; datum absoluto de proceso provisional","status":"derivado"},{"label":"Cota superior de visualización","value":286.3,"unit":"m","source":"Geometría releída del IFC; datum absoluto de proceso provisional","status":"derivado"}]} | [] | {"Cota inferior relativa (m)":0.18000000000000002,"Cota superior relativa (m)":0.2,"Cero absoluto de visualización (m)":286.1,"Estado del cero absoluto":"Provisional","Criterio":"Las cotas relativas proceden del dibujo; la equivalencia absoluta no está confirmada."} | SUP-C25 | [] | ["C25"] | ZD1 / DZ-1 | ["2CCDA","2CD54","2CCF2","2CD96","2CCE3","2CCE4","2CD78","2CEBB","2CE96"] | SUP-C25/Cimentación de soporte de tuberías C25 · placa embebida MJ-1 | {"boundingBoxM":{"min":[60.519849,52.230434,1.28],"max":[60.970603,52.681188,1.3]},"extentsM":[0.450754,0.450754,0.02],"meshSurfaceM2":0.352,"meshVolumeM3":0.0032,"closedSolid":true,"basis":"Magnitudes de las mallas representadas, no cantidades certificadas de obra, compra o fabricación. Las partes pueden compartir superficies; no se suman como un despiece de materiales."} | {"elementId":"found_0904_962f93347851e0","ifcGuid":"0RY4ZKWlXGW9JLSC_VTkzB","ifcClass":"IfcPlate","buildingId":"process_plant","buildingName":"Zona de separación de aire","sourceDocumentId":"LHD2609-JG00100-20260904","sourceRepresentationKind":"foundation"} | 2CCDA, 2CD54, 2CCF2, 2CD96, 2CCE3, 2CCE4, 2CD78, 2CEBB, 2CE96 | 0.18 | 0.2 | 0.16 | Contornos y sección documentados por el fabricante | found_0904_962f93347851e0 | 0.4 | 0.02 | M1: detalle20 mm; MJ1/MJ2:20 mm derivados del contorno lateral80 mm a escala4, no de una cota explícita. | C25 | Fz=-1500 | 24925.0 / 26075.0
Cimentación de soporte de tuberías C26 · placa embebida MJ-1 | 0.450754 | 0.450754 | 0.02 | 286.28 | 286.3 | 0.352 | 0.0032 | {"documentId":"LHD2609-JG00100-20260904","title":"Cimentaciones de equipos y pedestales del fabricante · revisión recibida 04/09/2026","date":"2026-09-04","sheet":"ZD1 / DZ-1","fileName":"LHD2609-JG00100_20260904.dwg","revisionCaveat":"Fecha de revisión tomada del nombre recibido; cajetines internos mantienen 02/07/2026 y algunos textos de plantilla.","sourceFileSha256":"b42eb027b7bc0b14c38d1d13514f4899b58a732aa8d0ba2ccf10fa2fc3192890"} | {"documented":[{"label":"Extensión local X","value":0.4,"unit":"m","source":"2CCDB, 2CD55, 2CCF3, 2CD97, 2CCE2, 2CCE5, 2CD79, 2CEBC, 2CE97","status":"derivada del contorno CAD"},{"label":"Extensión local Y","value":0.4,"unit":"m","source":"2CCDB, 2CD55, 2CCF3, 2CD97, 2CCE2, 2CCE5, 2CD79, 2CEBC, 2CE97","status":"derivada del contorno CAD"},{"label":"Cota inferior relativa adoptada","value":0.18000000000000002,"unit":"m","source":"ZD1 / DZ-1","status":"documentada"},{"label":"Cota superior relativa adoptada","value":0.2,"unit":"m","source":"ZD1 / DZ-1","status":"documentada / separación por material"}],"geometry":[{"label":"Extensión de la malla en X","value":0.45075400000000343,"unit":"m","source":"Geometría releída del IFC; datum absoluto de proceso provisional","status":"derivado"},{"label":"Extensión de la malla en Y","value":0.4507539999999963,"unit":"m","source":"Geometría releída del IFC; datum absoluto de proceso provisional","status":"derivado"},{"label":"Extensión de la malla en Z","value":0.020000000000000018,"unit":"m","source":"Geometría releída del IFC; datum absoluto de proceso provisional","status":"derivado"},{"label":"Cota inferior de visualización","value":286.28,"unit":"m","source":"Geometría releída del IFC; datum absoluto de proceso provisional","status":"derivado"},{"label":"Cota superior de visualización","value":286.3,"unit":"m","source":"Geometría releída del IFC; datum absoluto de proceso provisional","status":"derivado"}]} | [] | {"Cota inferior relativa (m)":0.18000000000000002,"Cota superior relativa (m)":0.2,"Cero absoluto de visualización (m)":286.1,"Estado del cero absoluto":"Provisional","Criterio":"Las cotas relativas proceden del dibujo; la equivalencia absoluta no está confirmada."} | SUP-C26 | [] | ["C26"] | ZD1 / DZ-1 | ["2CCDB","2CD55","2CCF3","2CD97","2CCE2","2CCE5","2CD79","2CEBC","2CE97"] | SUP-C26/Cimentación de soporte de tuberías C26 · placa embebida MJ-1 | {"boundingBoxM":{"min":[62.253541,51.992077,1.28],"max":[62.704295,52.442831,1.3]},"extentsM":[0.450754,0.450754,0.02],"meshSurfaceM2":0.352,"meshVolumeM3":0.0032,"closedSolid":true,"basis":"Magnitudes de las mallas representadas, no cantidades certificadas de obra, compra o fabricación. Las partes pueden compartir superficies; no se suman como un despiece de materiales."} | {"elementId":"found_0904_b2ac6c4a33bf3e","ifcGuid":"2ihuz62QXRy9Rmjls9vkWL","ifcClass":"IfcPlate","buildingId":"process_plant","buildingName":"Zona de separación de aire","sourceDocumentId":"LHD2609-JG00100-20260904","sourceRepresentationKind":"foundation"} | 2CCDB, 2CD55, 2CCF3, 2CD97, 2CCE2, 2CCE5, 2CD79, 2CEBC, 2CE97 | 0.18 | 0.2 | 0.16 | Contornos y sección documentados por el fabricante | found_0904_b2ac6c4a33bf3e | 0.4 | 0.02 | M1: detalle20 mm; MJ1/MJ2:20 mm derivados del contorno lateral80 mm a escala4, no de una cota explícita. | C26 | Fz=-1500 | 26675.0 / 26075.0
Cimentación de soporte de tuberías C27 · placa embebida MJ-1 | 0.450754 | 0.450754 | 0.02 | 286.28 | 286.3 | 0.352 | 0.0032 | {"documentId":"LHD2609-JG00100-20260904","title":"Cimentaciones de equipos y pedestales del fabricante · revisión recibida 04/09/2026","date":"2026-09-04","sheet":"ZD1 / DZ-1","fileName":"LHD2609-JG00100_20260904.dwg","revisionCaveat":"Fecha de revisión tomada del nombre recibido; cajetines internos mantienen 02/07/2026 y algunos textos de plantilla.","sourceFileSha256":"b42eb027b7bc0b14c38d1d13514f4899b58a732aa8d0ba2ccf10fa2fc3192890"} | {"documented":[{"label":"Extensión local X","value":0.4,"unit":"m","source":"2CCDC, 2CD56, 2CCF4, 2CD98, 2CCE6, 2CCE8, 2CD7A, 2CEBD, 2CE98","status":"derivada del contorno CAD"},{"label":"Extensión local Y","value":0.4,"unit":"m","source":"2CCDC, 2CD56, 2CCF4, 2CD98, 2CCE6, 2CCE8, 2CD7A, 2CEBD, 2CE98","status":"derivada del contorno CAD"},{"label":"Cota inferior relativa adoptada","value":0.18000000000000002,"unit":"m","source":"ZD1 / DZ-1","status":"documentada"},{"label":"Cota superior relativa adoptada","value":0.2,"unit":"m","source":"ZD1 / DZ-1","status":"documentada / separación por material"}],"geometry":[{"label":"Extensión de la malla en X","value":0.45075400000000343,"unit":"m","source":"Geometría releída del IFC; datum absoluto de proceso provisional","status":"derivado"},{"label":"Extensión de la malla en Y","value":0.4507539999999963,"unit":"m","source":"Geometría releída del IFC; datum absoluto de proceso provisional","status":"derivado"},{"label":"Extensión de la malla en Z","value":0.020000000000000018,"unit":"m","source":"Geometría releída del IFC; datum absoluto de proceso provisional","status":"derivado"},{"label":"Cota inferior de visualización","value":286.28,"unit":"m","source":"Geometría releída del IFC; datum absoluto de proceso provisional","status":"derivado"},{"label":"Cota superior de visualización","value":286.3,"unit":"m","source":"Geometría releída del IFC; datum absoluto de proceso provisional","status":"derivado"}]} | [] | {"Cota inferior relativa (m)":0.18000000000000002,"Cota superior relativa (m)":0.2,"Cero absoluto de visualización (m)":286.1,"Estado del cero absoluto":"Provisional","Criterio":"Las cotas relativas proceden del dibujo; la equivalencia absoluta no está confirmada."} | SUP-C27 | [] | ["C27"] | ZD1 / DZ-1 | ["2CCDC","2CD56","2CCF4","2CD98","2CCE6","2CCE8","2CD7A","2CEBD","2CE98"] | SUP-C27/Cimentación de soporte de tuberías C27 · placa embebida MJ-1 | {"boundingBoxM":{"min":[60.281492,50.496743,1.28],"max":[60.732246,50.947497,1.3]},"extentsM":[0.450754,0.450754,0.02],"meshSurfaceM2":0.352,"meshVolumeM3":0.0032,"closedSolid":true,"basis":"Magnitudes de las mallas representadas, no cantidades certificadas de obra, compra o fabricación. Las partes pueden compartir superficies; no se suman como un despiece de materiales."} | {"elementId":"found_0904_1b4f8e545510b9","ifcGuid":"3r_EZBmgbUhv7hfsRQ70$b","ifcClass":"IfcPlate","buildingId":"process_plant","buildingName":"Zona de separación de aire","sourceDocumentId":"LHD2609-JG00100-20260904","sourceRepresentationKind":"foundation"} | 2CCDC, 2CD56, 2CCF4, 2CD98, 2CCE6, 2CCE8, 2CD7A, 2CEBD, 2CE98 | 0.18 | 0.2 | 0.16 | Contornos y sección documentados por el fabricante | found_0904_1b4f8e545510b9 | 0.4 | 0.02 | M1: detalle20 mm; MJ1/MJ2:20 mm derivados del contorno lateral80 mm a escala4, no de una cota explícita. | C27 | Fz=-1500 | 24925.0 / 24325.0
Cimentación de soporte de tuberías C28 · placa embebida MJ-1 | 0.450754 | 0.450754 | 0.02 | 286.28 | 286.3 | 0.352 | 0.0032 | {"documentId":"LHD2609-JG00100-20260904","title":"Cimentaciones de equipos y pedestales del fabricante · revisión recibida 04/09/2026","date":"2026-09-04","sheet":"ZD1 / DZ-1","fileName":"LHD2609-JG00100_20260904.dwg","revisionCaveat":"Fecha de revisión tomada del nombre recibido; cajetines internos mantienen 02/07/2026 y algunos textos de plantilla.","sourceFileSha256":"b42eb027b7bc0b14c38d1d13514f4899b58a732aa8d0ba2ccf10fa2fc3192890"} | {"documented":[{"label":"Extensión local X","value":0.4,"unit":"m","source":"2CCDD, 2CD57, 2CCF5, 2CD99, 2CCE7, 2CCE9, 2CD7B, 2CEBE, 2CE99","status":"derivada del contorno CAD"},{"label":"Extensión local Y","value":0.4,"unit":"m","source":"2CCDD, 2CD57, 2CCF5, 2CD99, 2CCE7, 2CCE9, 2CD7B, 2CEBE, 2CE99","status":"derivada del contorno CAD"},{"label":"Cota inferior relativa adoptada","value":0.18000000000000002,"unit":"m","source":"ZD1 / DZ-1","status":"documentada"},{"label":"Cota superior relativa adoptada","value":0.2,"unit":"m","source":"ZD1 / DZ-1","status":"documentada / separación por material"}],"geometry":[{"label":"Extensión de la malla en X","value":0.45075400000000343,"unit":"m","source":"Geometría releída del IFC; datum absoluto de proceso provisional","status":"derivado"},{"label":"Extensión de la malla en Y","value":0.4507539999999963,"unit":"m","source":"Geometría releída del IFC; datum absoluto de proceso provisional","status":"derivado"},{"label":"Extensión de la malla en Z","value":0.020000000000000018,"unit":"m","source":"Geometría releída del IFC; datum absoluto de proceso provisional","status":"derivado"},{"label":"Cota inferior de visualización","value":286.28,"unit":"m","source":"Geometría releída del IFC; datum absoluto de proceso provisional","status":"derivado"},{"label":"Cota superior de visualización","value":286.3,"unit":"m","source":"Geometría releída del IFC; datum absoluto de proceso provisional","status":"derivado"}]} | [] | {"Cota inferior relativa (m)":0.18000000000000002,"Cota superior relativa (m)":0.2,"Cero absoluto de visualización (m)":286.1,"Estado del cero absoluto":"Provisional","Criterio":"Las cotas relativas proceden del dibujo; la equivalencia absoluta no está confirmada."} | SUP-C28 | [] | ["C28"] | ZD1 / DZ-1 | ["2CCDD","2CD57","2CCF5","2CD99","2CCE7","2CCE9","2CD7B","2CEBE","2CE99"] | SUP-C28/Cimentación de soporte de tuberías C28 · placa embebida MJ-1 | {"boundingBoxM":{"min":[62.015184,50.258386,1.28],"max":[62.465938,50.70914,1.3]},"extentsM":[0.450754,0.450754,0.02],"meshSurfaceM2":0.352,"meshVolumeM3":0.0032,"closedSolid":true,"basis":"Magnitudes de las mallas representadas, no cantidades certificadas de obra, compra o fabricación. Las partes pueden compartir superficies; no se suman como un despiece de materiales."} | {"elementId":"found_0904_2eb1daa04dbdce","ifcGuid":"0jF_EEL_TVYAeKKTmhRrRp","ifcClass":"IfcPlate","buildingId":"process_plant","buildingName":"Zona de separación de aire","sourceDocumentId":"LHD2609-JG00100-20260904","sourceRepresentationKind":"foundation"} | 2CCDD, 2CD57, 2CCF5, 2CD99, 2CCE7, 2CCE9, 2CD7B, 2CEBE, 2CE99 | 0.18 | 0.2 | 0.16 | Contornos y sección documentados por el fabricante | found_0904_2eb1daa04dbdce | 0.4 | 0.02 | M1: detalle20 mm; MJ1/MJ2:20 mm derivados del contorno lateral80 mm a escala4, no de una cota explícita. | C28 | Fz=-1500 | 26675.0 / 24325.0
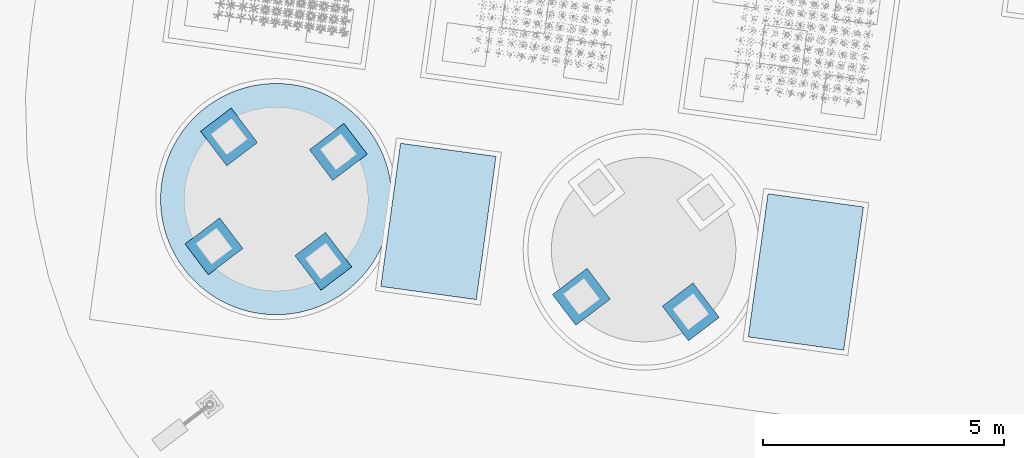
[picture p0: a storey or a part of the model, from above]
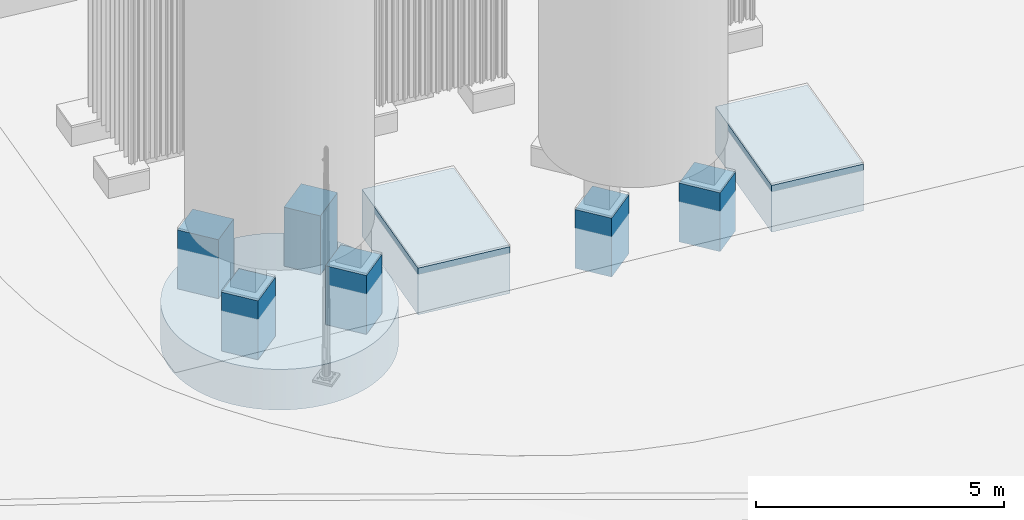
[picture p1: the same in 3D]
Properties of the parts of a building model (IFC4), part 100 of 134

# IfcPlate: Cimentación industrial (48)
Name | Extensión de la malla en X (m) = ExtensionX (m) | Extensión de la malla en Y (m) = ExtensionY (m) | Extensión de la malla en Z (m) = ExtensionZ (m) = Espesor o altura real de sección (m) | Cota inferior de visualización (m) | Cota superior de visualización (m) | SuperficieDeLaMalla (m2) | VolumenGeometrico (m3) = Volumen geométrico (m³) | source = DocumentoFuente | dimensions | issues = IncidenciasPendientes | positioning = PosicionYEstado | assemblyId = Conjunto de cimentación | equipmentIds | supportPositionIds | sectionRef = Sección de referencia | sourceCadHandles | stableElementKey | geometryMetrics | visualizationIdentity | Identificadores CAD de referencia | Cota inferior relativa (m) = Cota inferior relativa adoptada (m) | Cota superior relativa (m) = Cota superior relativa adoptada (m) | Área de planta (m²) | Estado de la geometría | Identificador | Extensión local X (m) = Extensión local Y (m) | Espesor de placa (m) | Origen del espesor de placa | Código original en tabla | Carga vertical indicada | Posición E/N de la tabla (mm)
Cimentación de soporte de tuberías C29 · placa embebida MJ-2 | 0.507098 | 0.507099 | 0.02 | 286.28 | 286.3 | 0.441001 | 0.00405 | {"documentId":"LHD2609-JG00100-20260904","title":"Cimentaciones de equipos y pedestales del fabricante · revisión recibida 04/09/2026","date":"2026-09-04","sheet":"ZD1 / DZ-2","fileName":"LHD2609-JG00100_20260904.dwg","revisionCaveat":"Fecha de revisión tomada del nombre recibido; cajetines internos mantienen 02/07/2026 y algunos textos de plantilla.","sourceFileSha256":"b42eb027b7bc0b14c38d1d13514f4899b58a732aa8d0ba2ccf10fa2fc3192890"} | {"documented":[{"label":"Extensión local X","value":0.45,"unit":"m","source":"2CCDE, 2CD61, 2CCF6, 2CD9A, 2CCF1, 2CCEC, 2CD85, 2CEBF, 2CE9A","status":"derivada del contorno CAD"},{"label":"Extensión local Y","value":0.45,"unit":"m","source":"2CCDE, 2CD61, 2CCF6, 2CD9A, 2CCF1, 2CCEC, 2CD85, 2CEBF, 2CE9A","status":"derivada del contorno CAD"},{"label":"Cota inferior relativa adoptada","value":0.18000000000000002,"unit":"m","source":"ZD1 / DZ-2","status":"documentada"},{"label":"Cota superior relativa adoptada","value":0.2,"unit":"m","source":"ZD1 / DZ-2","status":"documentada / separación por material"}],"geometry":[{"label":"Extensión de la malla en X","value":0.5070979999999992,"unit":"m","source":"Geometría releída del IFC; datum absoluto de proceso provisional","status":"derivado"},{"label":"Extensión de la malla en Y","value":0.5070990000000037,"unit":"m","source":"Geometría releída del IFC; datum absoluto de proceso provisional","status":"derivado"},{"label":"Extensión de la malla en Z","value":0.020000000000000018,"unit":"m","source":"Geometría releída del IFC; datum absoluto de proceso provisional","status":"derivado"},{"label":"Cota inferior de visualización","value":286.28,"unit":"m","source":"Geometría releída del IFC; datum absoluto de proceso provisional","status":"derivado"},{"label":"Cota superior de visualización","value":286.3,"unit":"m","source":"Geometría releída del IFC; datum absoluto de proceso provisional","status":"derivado"}]} | [] | {"Cota inferior relativa (m)":0.18000000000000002,"Cota superior relativa (m)":0.2,"Cero absoluto de visualización (m)":286.1,"Estado del cero absoluto":"Provisional","Criterio":"Las cotas relativas proceden del dibujo; la equivalencia absoluta no está confirmada."} | SUP-C29 | [] | ["C29"] | ZD1 / DZ-2 | ["2CCDE","2CD61","2CCF6","2CD9A","2CCF1","2CCEC","2CD85","2CEBF","2CE9A"] | SUP-C29/Cimentación de soporte de tuberías C29 · placa embebida MJ-2 | {"boundingBoxM":{"min":[43.12048,49.013571,1.28],"max":[43.627578,49.52067,1.3]},"extentsM":[0.507098,0.507099,0.02],"meshSurfaceM2":0.441001,"meshVolumeM3":0.00405,"closedSolid":true,"basis":"Magnitudes de las mallas representadas, no cantidades certificadas de obra, compra o fabricación. Las partes pueden compartir superficies; no se suman como un despiece de materiales."} | {"elementId":"found_0904_c12fb45daa6cfa","ifcGuid":"3qvTKoXX9S99h3T4dxKsh4","ifcClass":"IfcPlate","buildingId":"process_plant","buildingName":"Zona de separación de aire","sourceDocumentId":"LHD2609-JG00100-20260904","sourceRepresentationKind":"foundation"} | 2CCDE, 2CD61, 2CCF6, 2CD9A, 2CCF1, 2CCEC, 2CD85, 2CEBF, 2CE9A | 0.18 | 0.2 | 0.2025 | Contornos y sección documentados por el fabricante | found_0904_c12fb45daa6cfa | 0.45 | 0.02 | M1: detalle20 mm; MJ1/MJ2:20 mm derivados del contorno lateral80 mm a escala4, no de una cota explícita. | C29 | Fz=-3000 | 8150.0 / 20550.0
Cimentación de soporte de tuberías C30 · placa embebida MJ-2 | 0.507098 | 0.507098 | 0.02 | 286.28 | 286.3 | 0.440999 | 0.00405 | {"documentId":"LHD2609-JG00100-20260904","title":"Cimentaciones de equipos y pedestales del fabricante · revisión recibida 04/09/2026","date":"2026-09-04","sheet":"ZD1 / DZ-2","fileName":"LHD2609-JG00100_20260904.dwg","revisionCaveat":"Fecha de revisión tomada del nombre recibido; cajetines internos mantienen 02/07/2026 y algunos textos de plantilla.","sourceFileSha256":"b42eb027b7bc0b14c38d1d13514f4899b58a732aa8d0ba2ccf10fa2fc3192890"} | {"documented":[{"label":"Extensión local X","value":0.45,"unit":"m","source":"2CCDF, 2CD62, 2CCF7, 2CD9B, 2CCEF, 2CCF0, 2CD86, 2CEC0, 2CE9B","status":"derivada del contorno CAD"},{"label":"Extensión local Y","value":0.45,"unit":"m","source":"2CCDF, 2CD62, 2CCF7, 2CD9B, 2CCEF, 2CCF0, 2CD86, 2CEC0, 2CE9B","status":"derivada del contorno CAD"},{"label":"Cota inferior relativa adoptada","value":0.18000000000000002,"unit":"m","source":"ZD1 / DZ-2","status":"interpretación con conflicto conservado"},{"label":"Cota superior relativa adoptada","value":0.2,"unit":"m","source":"ZD1 / DZ-2","status":"documentada / separación por material"}],"geometry":[{"label":"Extensión de la malla en X","value":0.5070979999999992,"unit":"m","source":"Geometría releída del IFC; datum absoluto de proceso provisional","status":"derivado"},{"label":"Extensión de la malla en Y","value":0.5070979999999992,"unit":"m","source":"Geometría releída del IFC; datum absoluto de proceso provisional","status":"derivado"},{"label":"Extensión de la malla en Z","value":0.020000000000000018,"unit":"m","source":"Geometría releída del IFC; datum absoluto de proceso provisional","status":"derivado"},{"label":"Cota inferior de visualización","value":286.28,"unit":"m","source":"Geometría releída del IFC; datum absoluto de proceso provisional","status":"derivado"},{"label":"Cota superior de visualización","value":286.3,"unit":"m","source":"Geometría releída del IFC; datum absoluto de proceso provisional","status":"derivado"}]} | ["Identificador original HA-30 en columna de posición; C30 se infiere por secuencia. Se conserva el original y no se interpreta como material."] | {"Cota inferior relativa (m)":0.18000000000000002,"Cota superior relativa (m)":0.2,"Cero absoluto de visualización (m)":286.1,"Estado del cero absoluto":"Provisional","Criterio":"Las cotas relativas proceden del dibujo; la equivalencia absoluta no está confirmada."} | SUP-C30 | [] | ["C30"] | ZD1 / DZ-2 | ["2CCDF","2CD62","2CCF7","2CD9B","2CCEF","2CCF0","2CD86","2CEC0","2CE9B"] | SUP-C30/Cimentación de soporte de tuberías C30 · placa embebida MJ-2 | {"boundingBoxM":{"min":[42.371358,43.564827,1.28],"max":[42.878456,44.071925,1.3]},"extentsM":[0.507098,0.507098,0.02],"meshSurfaceM2":0.440999,"meshVolumeM3":0.00405,"closedSolid":true,"basis":"Magnitudes de las mallas representadas, no cantidades certificadas de obra, compra o fabricación. Las partes pueden compartir superficies; no se suman como un despiece de materiales."} | {"elementId":"found_0904_c78c40586d18fe","ifcGuid":"2Iyyfa33jT0Al0c0usS2nA","ifcClass":"IfcPlate","buildingId":"process_plant","buildingName":"Zona de separación de aire","sourceDocumentId":"LHD2609-JG00100-20260904","sourceRepresentationKind":"foundation"} | 2CCDF, 2CD62, 2CCF7, 2CD9B, 2CCEF, 2CCF0, 2CD86, 2CEC0, 2CE9B | 0.18 | 0.2 | 0.2025 | Sección y contornos del fabricante; incidencias conservadas | found_0904_c78c40586d18fe | 0.45 | 0.02 | M1: detalle20 mm; MJ1/MJ2:20 mm derivados del contorno lateral80 mm a escala4, no de una cota explícita. | HA-30 | Fz=-2000 | 8150.0 / 15050.0 | JH_Trazabilidad - Incidencias de origen: Identificador original HA-30 en columna de posición; C30 se infiere por secuencia. Se conserva el original y no se interpreta como material.
Cimentación de soporte de tuberías C31 · placa embebida MJ-2 | 0.507099 | 0.507098 | 0.02 | 286.28 | 286.3 | 0.441001 | 0.00405 | {"documentId":"LHD2609-JG00100-20260904","title":"Cimentaciones de equipos y pedestales del fabricante · revisión recibida 04/09/2026","date":"2026-09-04","sheet":"ZD1 / DZ-2","fileName":"LHD2609-JG00100_20260904.dwg","revisionCaveat":"Fecha de revisión tomada del nombre recibido; cajetines internos mantienen 02/07/2026 y algunos textos de plantilla.","sourceFileSha256":"b42eb027b7bc0b14c38d1d13514f4899b58a732aa8d0ba2ccf10fa2fc3192890"} | {"documented":[{"label":"Extensión local X","value":0.45,"unit":"m","source":"2CCE0, 2CD63, 2CCF8, 2CD9C, 2CCED, 2CCEE, 2CD87, 2CEC1, 2CE9C","status":"derivada del contorno CAD"},{"label":"Extensión local Y","value":0.45,"unit":"m","source":"2CCE0, 2CD63, 2CCF8, 2CD9C, 2CCED, 2CCEE, 2CD87, 2CEC1, 2CE9C","status":"derivada del contorno CAD"},{"label":"Cota inferior relativa adoptada","value":0.18000000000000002,"unit":"m","source":"ZD1 / DZ-2","status":"documentada"},{"label":"Cota superior relativa adoptada","value":0.2,"unit":"m","source":"ZD1 / DZ-2","status":"documentada / separación por material"}],"geometry":[{"label":"Extensión de la malla en X","value":0.5070990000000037,"unit":"m","source":"Geometría releída del IFC; datum absoluto de proceso provisional","status":"derivado"},{"label":"Extensión de la malla en Y","value":0.5070979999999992,"unit":"m","source":"Geometría releída del IFC; datum absoluto de proceso provisional","status":"derivado"},{"label":"Extensión de la malla en Z","value":0.020000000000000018,"unit":"m","source":"Geometría releída del IFC; datum absoluto de proceso provisional","status":"derivado"},{"label":"Cota inferior de visualización","value":286.28,"unit":"m","source":"Geometría releída del IFC; datum absoluto de proceso provisional","status":"derivado"},{"label":"Cota superior de visualización","value":286.3,"unit":"m","source":"Geometría releída del IFC; datum absoluto de proceso provisional","status":"derivado"}]} | [] | {"Cota inferior relativa (m)":0.18000000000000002,"Cota superior relativa (m)":0.2,"Cero absoluto de visualización (m)":286.1,"Estado del cero absoluto":"Provisional","Criterio":"Las cotas relativas proceden del dibujo; la equivalencia absoluta no está confirmada."} | SUP-C31 | [] | ["C31"] | ZD1 / DZ-2 | ["2CCE0","2CD63","2CCF8","2CD9C","2CCED","2CCEE","2CD87","2CEC1","2CE9C"] | SUP-C31/Cimentación de soporte de tuberías C31 · placa embebida MJ-2 | {"boundingBoxM":{"min":[47.059687,47.563523,1.28],"max":[47.566786,48.070621,1.3]},"extentsM":[0.507099,0.507098,0.02],"meshSurfaceM2":0.441001,"meshVolumeM3":0.00405,"closedSolid":true,"basis":"Magnitudes de las mallas representadas, no cantidades certificadas de obra, compra o fabricación. Las partes pueden compartir superficies; no se suman como un despiece de materiales."} | {"elementId":"found_0904_59f3905f88acf6","ifcGuid":"1GPCdZBInLSeSkEsjmNtBv","ifcClass":"IfcPlate","buildingId":"process_plant","buildingName":"Zona de separación de aire","sourceDocumentId":"LHD2609-JG00100-20260904","sourceRepresentationKind":"foundation"} | 2CCE0, 2CD63, 2CCF8, 2CD9C, 2CCED, 2CCEE, 2CD87, 2CEC1, 2CE9C | 0.18 | 0.2 | 0.2025 | Contornos y sección documentados por el fabricante | found_0904_59f3905f88acf6 | 0.45 | 0.02 | M1: detalle20 mm; MJ1/MJ2:20 mm derivados del contorno lateral80 mm a escala4, no de una cota explícita. | C31 | Fz=-1500 | 12250.0 / 19650.0
Cimentación de soporte de tuberías C32 · placa embebida MJ-2 | 0.507098 | 0.507099 | 0.02 | 286.28 | 286.3 | 0.441001 | 0.00405 | {"documentId":"LHD2609-JG00100-20260904","title":"Cimentaciones de equipos y pedestales del fabricante · revisión recibida 04/09/2026","date":"2026-09-04","sheet":"ZD1 / DZ-2","fileName":"LHD2609-JG00100_20260904.dwg","revisionCaveat":"Fecha de revisión tomada del nombre recibido; cajetines internos mantienen 02/07/2026 y algunos textos de plantilla.","sourceFileSha256":"b42eb027b7bc0b14c38d1d13514f4899b58a732aa8d0ba2ccf10fa2fc3192890"} | {"documented":[{"label":"Extensión local X","value":0.45,"unit":"m","source":"2CCE1, 2CD64, 2CCF9, 2CD9D, 2CCEA, 2CCEB, 2CD88, 2CEC2, 2CE9D","status":"derivada del contorno CAD"},{"label":"Extensión local Y","value":0.45,"unit":"m","source":"2CCE1, 2CD64, 2CCF9, 2CD9D, 2CCEA, 2CCEB, 2CD88, 2CEC2, 2CE9D","status":"derivada del contorno CAD"},{"label":"Cota inferior relativa adoptada","value":0.18000000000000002,"unit":"m","source":"ZD1 / DZ-2","status":"documentada"},{"label":"Cota superior relativa adoptada","value":0.2,"unit":"m","source":"ZD1 / DZ-2","status":"documentada / separación por material"}],"geometry":[{"label":"Extensión de la malla en X","value":0.5070979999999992,"unit":"m","source":"Geometría releída del IFC; datum absoluto de proceso provisional","status":"derivado"},{"label":"Extensión de la malla en Y","value":0.5070989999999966,"unit":"m","source":"Geometría releída del IFC; datum absoluto de proceso provisional","status":"derivado"},{"label":"Extensión de la malla en Z","value":0.020000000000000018,"unit":"m","source":"Geometría releída del IFC; datum absoluto de proceso provisional","status":"derivado"},{"label":"Cota inferior de visualización","value":286.28,"unit":"m","source":"Geometría releída del IFC; datum absoluto de proceso provisional","status":"derivado"},{"label":"Cota superior de visualización","value":286.3,"unit":"m","source":"Geometría releída del IFC; datum absoluto de proceso provisional","status":"derivado"}]} | [] | {"Cota inferior relativa (m)":0.18000000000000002,"Cota superior relativa (m)":0.2,"Cero absoluto de visualización (m)":286.1,"Estado del cero absoluto":"Provisional","Criterio":"Las cotas relativas proceden del dibujo; la equivalencia absoluta no está confirmada."} | SUP-C32 | [] | ["C32"] | ZD1 / DZ-2 | ["2CCE1","2CD64","2CCF9","2CD9D","2CCEA","2CCEB","2CD88","2CEC2","2CE9D"] | SUP-C32/Cimentación de soporte de tuberías C32 · placa embebida MJ-2 | {"boundingBoxM":{"min":[46.705557,44.987752,1.28],"max":[47.212655,45.494851,1.3]},"extentsM":[0.507098,0.507099,0.02],"meshSurfaceM2":0.441001,"meshVolumeM3":0.00405,"closedSolid":true,"basis":"Magnitudes de las mallas representadas, no cantidades certificadas de obra, compra o fabricación. Las partes pueden compartir superficies; no se suman como un despiece de materiales."} | {"elementId":"found_0904_269d862a90b6dd","ifcGuid":"10BiALOc5VkOade53gMrxO","ifcClass":"IfcPlate","buildingId":"process_plant","buildingName":"Zona de separación de aire","sourceDocumentId":"LHD2609-JG00100-20260904","sourceRepresentationKind":"foundation"} | 2CCE1, 2CD64, 2CCF9, 2CD9D, 2CCEA, 2CCEB, 2CD88, 2CEC2, 2CE9D | 0.18 | 0.2 | 0.2025 | Contornos y sección documentados por el fabricante | found_0904_269d862a90b6dd | 0.45 | 0.02 | M1: detalle20 mm; MJ1/MJ2:20 mm derivados del contorno lateral80 mm a escala4, no de una cota explícita. | C32 | Fz=-1000 | 12250.0 / 17050.0
Cimentación de soporte de tuberías C33 · placa embebida MJ-2 | 0.507099 | 0.507098 | 0.02 | 286.18 | 286.2 | 0.441001 | 0.00405 | {"documentId":"LHD2609-JG00100-20260904","title":"Cimentaciones de equipos y pedestales del fabricante · revisión recibida 04/09/2026","date":"2026-09-04","sheet":"ZD1 / DZ-2","fileName":"LHD2609-JG00100_20260904.dwg","revisionCaveat":"Fecha de revisión tomada del nombre recibido; cajetines internos mantienen 02/07/2026 y algunos textos de plantilla.","sourceFileSha256":"b42eb027b7bc0b14c38d1d13514f4899b58a732aa8d0ba2ccf10fa2fc3192890"} | {"documented":[{"label":"Extensión local X","value":0.45,"unit":"m","source":"2CD0A, 2CD58, 2CD22, 2CD9E, 2CD13, 2CD14, 2CD89, 2CEC3, 2CE9E","status":"derivada del contorno CAD"},{"label":"Extensión local Y","value":0.45,"unit":"m","source":"2CD0A, 2CD58, 2CD22, 2CD9E, 2CD13, 2CD14, 2CD89, 2CEC3, 2CE9E","status":"derivada del contorno CAD"},{"label":"Cota inferior relativa adoptada","value":0.08,"unit":"m","source":"ZD1 / DZ-2","status":"documentada"},{"label":"Cota superior relativa adoptada","value":0.1,"unit":"m","source":"ZD1 / DZ-2","status":"documentada / separación por material"}],"geometry":[{"label":"Extensión de la malla en X","value":0.5070989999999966,"unit":"m","source":"Geometría releída del IFC; datum absoluto de proceso provisional","status":"derivado"},{"label":"Extensión de la malla en Y","value":0.5070979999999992,"unit":"m","source":"Geometría releída del IFC; datum absoluto de proceso provisional","status":"derivado"},{"label":"Extensión de la malla en Z","value":0.020000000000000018,"unit":"m","source":"Geometría releída del IFC; datum absoluto de proceso provisional","status":"derivado"},{"label":"Cota inferior de visualización","value":286.18,"unit":"m","source":"Geometría releída del IFC; datum absoluto de proceso provisional","status":"derivado"},{"label":"Cota superior de visualización","value":286.2,"unit":"m","source":"Geometría releída del IFC; datum absoluto de proceso provisional","status":"derivado"}]} | [] | {"Cota inferior relativa (m)":0.08,"Cota superior relativa (m)":0.1,"Cero absoluto de visualización (m)":286.1,"Estado del cero absoluto":"Provisional","Criterio":"Las cotas relativas proceden del dibujo; la equivalencia absoluta no está confirmada."} | SUP-C33 | [] | ["C33"] | ZD1 / DZ-2 | ["2CD0A","2CD58","2CD22","2CD9E","2CD13","2CD14","2CD89","2CEC3","2CE9E"] | SUP-C33/Cimentación de soporte de tuberías C33 · placa embebida MJ-2 | {"boundingBoxM":{"min":[51.013097,48.786449,1.18],"max":[51.520196,49.293547,1.2]},"extentsM":[0.507099,0.507098,0.02],"meshSurfaceM2":0.441001,"meshVolumeM3":0.00405,"closedSolid":true,"basis":"Magnitudes de las mallas representadas, no cantidades certificadas de obra, compra o fabricación. Las partes pueden compartir superficies; no se suman como un despiece de materiales."} | {"elementId":"found_0904_d45da7c28766e5","ifcGuid":"2AB0E6AqfNW9Af34NlXRyv","ifcClass":"IfcPlate","buildingId":"process_plant","buildingName":"Zona de separación de aire","sourceDocumentId":"LHD2609-JG00100-20260904","sourceRepresentationKind":"foundation"} | 2CD0A, 2CD58, 2CD22, 2CD9E, 2CD13, 2CD14, 2CD89, 2CEC3, 2CE9E | 0.08 | 0.1 | 0.2025 | Contornos y sección documentados por el fabricante | found_0904_d45da7c28766e5 | 0.45 | 0.02 | M1: detalle20 mm; MJ1/MJ2:20 mm derivados del contorno lateral80 mm a escala4, no de una cota explícita. | C33 | Fz=-2500 | 16000.0 / 21400.0 | JH_InformacionBIM - conceptualReferenceIds: ["C33-CONCEPT-POST","C33-CONCEPT-BEAM","C33-CONCEPT-BRACE-W","C33-CONCEPT-BRACE-E","C33-CONCEPT-PIPE-01","C33-CONCEPT-PIPE-02"]; JH_ReferenciasDeEsquema - ObjetosIlustrativos: ["C33-CONCEPT-POST","C33-CONCEPT-BEAM","C33-CONCEPT-BRACE-W","C33-CONCEPT-BRACE-E","C33-CONCEPT-PIPE-01","C33-CONCEPT-PIPE-02"]; Nota: Relación de visualización, no conexión de montaje aprobada.
Cimentación de soporte de tuberías C34 · placa embebida MJ-2 | 0.507098 | 0.507098 | 0.02 | 286.28 | 286.3 | 0.441 | 0.00405 | {"documentId":"LHD2609-JG00100-20260904","title":"Cimentaciones de equipos y pedestales del fabricante · revisión recibida 04/09/2026","date":"2026-09-04","sheet":"ZD1 / DZ-2","fileName":"LHD2609-JG00100_20260904.dwg","revisionCaveat":"Fecha de revisión tomada del nombre recibido; cajetines internos mantienen 02/07/2026 y algunos textos de plantilla.","sourceFileSha256":"b42eb027b7bc0b14c38d1d13514f4899b58a732aa8d0ba2ccf10fa2fc3192890"} | {"documented":[{"label":"Extensión local X","value":0.45,"unit":"m","source":"2CD0B, 2CD66, 2CD23, 2CD9F, 2CD12, 2CD15, 2CD8A, 2CEC4, 2CE9F","status":"derivada del contorno CAD"},{"label":"Extensión local Y","value":0.45,"unit":"m","source":"2CD0B, 2CD66, 2CD23, 2CD9F, 2CD12, 2CD15, 2CD8A, 2CEC4, 2CE9F","status":"derivada del contorno CAD"},{"label":"Cota inferior relativa adoptada","value":0.18000000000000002,"unit":"m","source":"ZD1 / DZ-2","status":"documentada"},{"label":"Cota superior relativa adoptada","value":0.2,"unit":"m","source":"ZD1 / DZ-2","status":"documentada / separación por material"}],"geometry":[{"label":"Extensión de la malla en X","value":0.5070979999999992,"unit":"m","source":"Geometría releída del IFC; datum absoluto de proceso provisional","status":"derivado"},{"label":"Extensión de la malla en Y","value":0.5070979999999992,"unit":"m","source":"Geometría releída del IFC; datum absoluto de proceso provisional","status":"derivado"},{"label":"Extensión de la malla en Z","value":0.020000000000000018,"unit":"m","source":"Geometría releída del IFC; datum absoluto de proceso provisional","status":"derivado"},{"label":"Cota inferior de visualización","value":286.28,"unit":"m","source":"Geometría releída del IFC; datum absoluto de proceso provisional","status":"derivado"},{"label":"Cota superior de visualización","value":286.3,"unit":"m","source":"Geometría releída del IFC; datum absoluto de proceso provisional","status":"derivado"}]} | [] | {"Cota inferior relativa (m)":0.18000000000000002,"Cota superior relativa (m)":0.2,"Cero absoluto de visualización (m)":286.1,"Estado del cero absoluto":"Provisional","Criterio":"Las cotas relativas proceden del dibujo; la equivalencia absoluta no está confirmada."} | SUP-C34 | [] | ["C34"] | ZD1 / DZ-2 | ["2CD0B","2CD66","2CD23","2CD9F","2CD12","2CD15","2CD8A","2CEC4","2CE9F"] | SUP-C34/Cimentación de soporte de tuberías C34 · placa embebida MJ-2 | {"boundingBoxM":{"min":[59.908213,44.838104,1.28],"max":[60.415311,45.345202,1.3]},"extentsM":[0.507098,0.507098,0.02],"meshSurfaceM2":0.441,"meshVolumeM3":0.00405,"closedSolid":true,"basis":"Magnitudes de las mallas representadas, no cantidades certificadas de obra, compra o fabricación. Las partes pueden compartir superficies; no se suman como un despiece de materiales."} | {"elementId":"found_0904_6afb836d968706","ifcGuid":"0ilA3Y9EjS08pIvT6DzR8l","ifcClass":"IfcPlate","buildingId":"process_plant","buildingName":"Zona de separación de aire","sourceDocumentId":"LHD2609-JG00100-20260904","sourceRepresentationKind":"foundation"} | 2CD0B, 2CD66, 2CD23, 2CD9F, 2CD12, 2CD15, 2CD8A, 2CEC4, 2CE9F | 0.18 | 0.2 | 0.2025 | Contornos y sección documentados por el fabricante | found_0904_6afb836d968706 | 0.45 | 0.02 | M1: detalle20 mm; MJ1/MJ2:20 mm derivados del contorno lateral80 mm a escala4, no de una cota explícita. | C34 | Fz=-1000 | 25350.0 / 18700.0
Cimentación de soporte de tuberías C35 · placa embebida MJ-2 | 0.507098 | 0.507098 | 0.02 | 286.28 | 286.3 | 0.441 | 0.00405 | {"documentId":"LHD2609-JG00100-20260904","title":"Cimentaciones de equipos y pedestales del fabricante · revisión recibida 04/09/2026","date":"2026-09-04","sheet":"ZD1 / DZ-2","fileName":"LHD2609-JG00100_20260904.dwg","revisionCaveat":"Fecha de revisión tomada del nombre recibido; cajetines internos mantienen 02/07/2026 y algunos textos de plantilla.","sourceFileSha256":"b42eb027b7bc0b14c38d1d13514f4899b58a732aa8d0ba2ccf10fa2fc3192890"} | {"documented":[{"label":"Extensión local X","value":0.45,"unit":"m","source":"2CD0C, 2CD65, 2CD24, 2CDA0, 2CD16, 2CD18, 2CD8B, 2CEC5, 2CEA0","status":"derivada del contorno CAD"},{"label":"Extensión local Y","value":0.45,"unit":"m","source":"2CD0C, 2CD65, 2CD24, 2CDA0, 2CD16, 2CD18, 2CD8B, 2CEC5, 2CEA0","status":"derivada del contorno CAD"},{"label":"Cota inferior relativa adoptada","value":0.18000000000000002,"unit":"m","source":"ZD1 / DZ-2","status":"interpretación con conflicto conservado"},{"label":"Cota superior relativa adoptada","value":0.2,"unit":"m","source":"ZD1 / DZ-2","status":"documentada / separación por material"}],"geometry":[{"label":"Extensión de la malla en X","value":0.5070979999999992,"unit":"m","source":"Geometría releída del IFC; datum absoluto de proceso provisional","status":"derivado"},{"label":"Extensión de la malla en Y","value":0.5070979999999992,"unit":"m","source":"Geometría releída del IFC; datum absoluto de proceso provisional","status":"derivado"},{"label":"Extensión de la malla en Z","value":0.020000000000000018,"unit":"m","source":"Geometría releída del IFC; datum absoluto de proceso provisional","status":"derivado"},{"label":"Cota inferior de visualización","value":286.28,"unit":"m","source":"Geometría releída del IFC; datum absoluto de proceso provisional","status":"derivado"},{"label":"Cota superior de visualización","value":286.3,"unit":"m","source":"Geometría releída del IFC; datum absoluto de proceso provisional","status":"derivado"}]} | ["Identificador original HA-35 en columna de posición; C35 se infiere por secuencia. Se conserva el original y no se interpreta como material."] | {"Cota inferior relativa (m)":0.18000000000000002,"Cota superior relativa (m)":0.2,"Cero absoluto de visualización (m)":286.1,"Estado del cero absoluto":"Provisional","Criterio":"Las cotas relativas proceden del dibujo; la equivalencia absoluta no está confirmada."} | SUP-C35 | [] | ["C35"] | ZD1 / DZ-2 | ["2CD0C","2CD65","2CD24","2CDA0","2CD16","2CD18","2CD8B","2CEC5","2CEA0"] | SUP-C35/Cimentación de soporte de tuberías C35 · placa embebida MJ-2 | {"boundingBoxM":{"min":[60.849359,44.708711,1.28],"max":[61.356457,45.215809,1.3]},"extentsM":[0.507098,0.507098,0.02],"meshSurfaceM2":0.441,"meshVolumeM3":0.00405,"closedSolid":true,"basis":"Magnitudes de las mallas representadas, no cantidades certificadas de obra, compra o fabricación. Las partes pueden compartir superficies; no se suman como un despiece de materiales."} | {"elementId":"found_0904_9e9da7e0eb59e7","ifcGuid":"1vQvgO80POFepfXvLMDb8B","ifcClass":"IfcPlate","buildingId":"process_plant","buildingName":"Zona de separación de aire","sourceDocumentId":"LHD2609-JG00100-20260904","sourceRepresentationKind":"foundation"} | 2CD0C, 2CD65, 2CD24, 2CDA0, 2CD16, 2CD18, 2CD8B, 2CEC5, 2CEA0 | 0.18 | 0.2 | 0.2025 | Sección y contornos del fabricante; incidencias conservadas | found_0904_9e9da7e0eb59e7 | 0.45 | 0.02 | M1: detalle20 mm; MJ1/MJ2:20 mm derivados del contorno lateral80 mm a escala4, no de una cota explícita. | HA-35 | Fz=-1000 | 26300.0 / 18700.0 | JH_Trazabilidad - Incidencias de origen: Identificador original HA-35 en columna de posición; C35 se infiere por secuencia. Se conserva el original y no se interpreta como material.
Cimentación de soporte de tuberías C36 · placa embebida MJ-1 | 0.450754 | 0.450754 | 0.02 | 286.28 | 286.3 | 0.352 | 0.0032 | {"documentId":"LHD2609-JG00100-20260904","title":"Cimentaciones de equipos y pedestales del fabricante · revisión recibida 04/09/2026","date":"2026-09-04","sheet":"ZD1 / DZ-1","fileName":"LHD2609-JG00100_20260904.dwg","revisionCaveat":"Fecha de revisión tomada del nombre recibido; cajetines internos mantienen 02/07/2026 y algunos textos de plantilla.","sourceFileSha256":"b42eb027b7bc0b14c38d1d13514f4899b58a732aa8d0ba2ccf10fa2fc3192890"} | {"documented":[{"label":"Extensión local X","value":0.4,"unit":"m","source":"2CD0D, 2CD59, 2CD25, 2CDA1, 2CD17, 2CD19, 2CD7C, 2CEC6, 2CEA1","status":"derivada del contorno CAD"},{"label":"Extensión local Y","value":0.4,"unit":"m","source":"2CD0D, 2CD59, 2CD25, 2CDA1, 2CD17, 2CD19, 2CD7C, 2CEC6, 2CEA1","status":"derivada del contorno CAD"},{"label":"Cota inferior relativa adoptada","value":0.18000000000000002,"unit":"m","source":"ZD1 / DZ-1","status":"documentada"},{"label":"Cota superior relativa adoptada","value":0.2,"unit":"m","source":"ZD1 / DZ-1","status":"documentada / separación por material"}],"geometry":[{"label":"Extensión de la malla en X","value":0.45075400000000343,"unit":"m","source":"Geometría releída del IFC; datum absoluto de proceso provisional","status":"derivado"},{"label":"Extensión de la malla en Y","value":0.45075400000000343,"unit":"m","source":"Geometría releída del IFC; datum absoluto de proceso provisional","status":"derivado"},{"label":"Extensión de la malla en Z","value":0.020000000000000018,"unit":"m","source":"Geometría releída del IFC; datum absoluto de proceso provisional","status":"derivado"},{"label":"Cota inferior de visualización","value":286.28,"unit":"m","source":"Geometría releída del IFC; datum absoluto de proceso provisional","status":"derivado"},{"label":"Cota superior de visualización","value":286.3,"unit":"m","source":"Geometría releída del IFC; datum absoluto de proceso provisional","status":"derivado"}]} | [] | {"Cota inferior relativa (m)":0.18000000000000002,"Cota superior relativa (m)":0.2,"Cero absoluto de visualización (m)":286.1,"Estado del cero absoluto":"Provisional","Criterio":"Las cotas relativas proceden del dibujo; la equivalencia absoluta no está confirmada."} | SUP-C36 | [] | ["C36"] | ZD1 / DZ-1 | ["2CD0D","2CD59","2CD25","2CDA1","2CD17","2CD19","2CD7C","2CEC6","2CEA1"] | SUP-C36/Cimentación de soporte de tuberías C36 · placa embebida MJ-1 | {"boundingBoxM":{"min":[59.398961,43.526995,1.28],"max":[59.849715,43.977749,1.3]},"extentsM":[0.450754,0.450754,0.02],"meshSurfaceM2":0.352,"meshVolumeM3":0.0032,"closedSolid":true,"basis":"Magnitudes de las mallas representadas, no cantidades certificadas de obra, compra o fabricación. Las partes pueden compartir superficies; no se suman como un despiece de materiales."} | {"elementId":"found_0904_960182305bec08","ifcGuid":"0mIvVJpG5GkgBwgWQMsNgl","ifcClass":"IfcPlate","buildingId":"process_plant","buildingName":"Zona de separación de aire","sourceDocumentId":"LHD2609-JG00100-20260904","sourceRepresentationKind":"foundation"} | 2CD0D, 2CD59, 2CD25, 2CDA1, 2CD17, 2CD19, 2CD7C, 2CEC6, 2CEA1 | 0.18 | 0.2 | 0.16 | Contornos y sección documentados por el fabricante | found_0904_960182305bec08 | 0.4 | 0.02 | M1: detalle20 mm; MJ1/MJ2:20 mm derivados del contorno lateral80 mm a escala4, no de una cota explícita. | C36 | Fz=-1500 | 25000.0 / 17300.0
Cimentación de soporte de tuberías C37 · placa embebida MJ-1 | 0.450754 | 0.450754 | 0.02 | 286.28 | 286.3 | 0.352 | 0.0032 | {"documentId":"LHD2609-JG00100-20260904","title":"Cimentaciones de equipos y pedestales del fabricante · revisión recibida 04/09/2026","date":"2026-09-04","sheet":"ZD1 / DZ-1","fileName":"LHD2609-JG00100_20260904.dwg","revisionCaveat":"Fecha de revisión tomada del nombre recibido; cajetines internos mantienen 02/07/2026 y algunos textos de plantilla.","sourceFileSha256":"b42eb027b7bc0b14c38d1d13514f4899b58a732aa8d0ba2ccf10fa2fc3192890"} | {"documented":[{"label":"Extensión local X","value":0.4,"unit":"m","source":"2CD0E, 2CD5A, 2CD26, 2CDA2, 2CD21, 2CD1C, 2CD7D, 2CEC7, 2CEA2","status":"derivada del contorno CAD"},{"label":"Extensión local Y","value":0.4,"unit":"m","source":"2CD0E, 2CD5A, 2CD26, 2CDA2, 2CD21, 2CD1C, 2CD7D, 2CEC7, 2CEA2","status":"derivada del contorno CAD"},{"label":"Cota inferior relativa adoptada","value":0.18000000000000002,"unit":"m","source":"ZD1 / DZ-1","status":"documentada"},{"label":"Cota superior relativa adoptada","value":0.2,"unit":"m","source":"ZD1 / DZ-1","status":"documentada / separación por material"}],"geometry":[{"label":"Extensión de la malla en X","value":0.4507539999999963,"unit":"m","source":"Geometría releída del IFC; datum absoluto de proceso provisional","status":"derivado"},{"label":"Extensión de la malla en Y","value":0.4507539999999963,"unit":"m","source":"Geometría releída del IFC; datum absoluto de proceso provisional","status":"derivado"},{"label":"Extensión de la malla en Z","value":0.020000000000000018,"unit":"m","source":"Geometría releída del IFC; datum absoluto de proceso provisional","status":"derivado"},{"label":"Cota inferior de visualización","value":286.28,"unit":"m","source":"Geometría releída del IFC; datum absoluto de proceso provisional","status":"derivado"},{"label":"Cota superior de visualización","value":286.3,"unit":"m","source":"Geometría releída del IFC; datum absoluto de proceso provisional","status":"derivado"}]} | [] | {"Cota inferior relativa (m)":0.18000000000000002,"Cota superior relativa (m)":0.2,"Cero absoluto de visualización (m)":286.1,"Estado del cero absoluto":"Provisional","Criterio":"Las cotas relativas proceden del dibujo; la equivalencia absoluta no está confirmada."} | SUP-C37 | [] | ["C37"] | ZD1 / DZ-1 | ["2CD0E","2CD5A","2CD26","2CDA2","2CD21","2CD1C","2CD7D","2CEC7","2CEA2"] | SUP-C37/Cimentación de soporte de tuberías C37 · placa embebida MJ-1 | {"boundingBoxM":{"min":[60.98405,43.309068,1.28],"max":[61.434804,43.759822,1.3]},"extentsM":[0.450754,0.450754,0.02],"meshSurfaceM2":0.352,"meshVolumeM3":0.0032,"closedSolid":true,"basis":"Magnitudes de las mallas representadas, no cantidades certificadas de obra, compra o fabricación. Las partes pueden compartir superficies; no se suman como un despiece de materiales."} | {"elementId":"found_0904_775a58d39fd275","ifcGuid":"359Kw1isLMGQ5pL_mOIWXN","ifcClass":"IfcPlate","buildingId":"process_plant","buildingName":"Zona de separación de aire","sourceDocumentId":"LHD2609-JG00100-20260904","sourceRepresentationKind":"foundation"} | 2CD0E, 2CD5A, 2CD26, 2CDA2, 2CD21, 2CD1C, 2CD7D, 2CEC7, 2CEA2 | 0.18 | 0.2 | 0.16 | Contornos y sección documentados por el fabricante | found_0904_775a58d39fd275 | 0.4 | 0.02 | M1: detalle20 mm; MJ1/MJ2:20 mm derivados del contorno lateral80 mm a escala4, no de una cota explícita. | C37 | Fz=-1500 | 26600.0 / 17300.0
Cimentación de soporte de tuberías C38 · placa embebida MJ-1 | 0.450754 | 0.450754 | 0.02 | 286.28 | 286.3 | 0.352 | 0.0032 | {"documentId":"LHD2609-JG00100-20260904","title":"Cimentaciones de equipos y pedestales del fabricante · revisión recibida 04/09/2026","date":"2026-09-04","sheet":"ZD1 / DZ-1","fileName":"LHD2609-JG00100_20260904.dwg","revisionCaveat":"Fecha de revisión tomada del nombre recibido; cajetines internos mantienen 02/07/2026 y algunos textos de plantilla.","sourceFileSha256":"b42eb027b7bc0b14c38d1d13514f4899b58a732aa8d0ba2ccf10fa2fc3192890"} | {"documented":[{"label":"Extensión local X","value":0.4,"unit":"m","source":"2CD0F, 2CD5B, 2CD27, 2CDA3, 2CD1F, 2CD20, 2CD7E, 2CEC8, 2CEA3","status":"derivada del contorno CAD"},{"label":"Extensión local Y","value":0.4,"unit":"m","source":"2CD0F, 2CD5B, 2CD27, 2CDA3, 2CD1F, 2CD20, 2CD7E, 2CEC8, 2CEA3","status":"derivada del contorno CAD"},{"label":"Cota inferior relativa adoptada","value":0.18000000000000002,"unit":"m","source":"ZD1 / DZ-1","status":"documentada"},{"label":"Cota superior relativa adoptada","value":0.2,"unit":"m","source":"ZD1 / DZ-1","status":"documentada / separación por material"}],"geometry":[{"label":"Extensión de la malla en X","value":0.4507539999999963,"unit":"m","source":"Geometría releída del IFC; datum absoluto de proceso provisional","status":"derivado"},{"label":"Extensión de la malla en Y","value":0.4507539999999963,"unit":"m","source":"Geometría releída del IFC; datum absoluto de proceso provisional","status":"derivado"},{"label":"Extensión de la malla en Z","value":0.020000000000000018,"unit":"m","source":"Geometría releída del IFC; datum absoluto de proceso provisional","status":"derivado"},{"label":"Cota inferior de visualización","value":286.28,"unit":"m","source":"Geometría releída del IFC; datum absoluto de proceso provisional","status":"derivado"},{"label":"Cota superior de visualización","value":286.3,"unit":"m","source":"Geometría releída del IFC; datum absoluto de proceso provisional","status":"derivado"}]} | [] | {"Cota inferior relativa (m)":0.18000000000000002,"Cota superior relativa (m)":0.2,"Cero absoluto de visualización (m)":286.1,"Estado del cero absoluto":"Provisional","Criterio":"Las cotas relativas proceden del dibujo; la equivalencia absoluta no está confirmada."} | SUP-C38 | [] | ["C38"] | ZD1 / DZ-1 | ["2CD0F","2CD5B","2CD27","2CDA3","2CD1F","2CD20","2CD7E","2CEC8","2CEA3"] | SUP-C38/Cimentación de soporte de tuberías C38 · placa embebida MJ-1 | {"boundingBoxM":{"min":[59.03121,40.852156,1.28],"max":[59.481964,41.30291,1.3]},"extentsM":[0.450754,0.450754,0.02],"meshSurfaceM2":0.352,"meshVolumeM3":0.0032,"closedSolid":true,"basis":"Magnitudes de las mallas representadas, no cantidades certificadas de obra, compra o fabricación. Las partes pueden compartir superficies; no se suman como un despiece de materiales."} | {"elementId":"found_0904_c9d35e22550ddd","ifcGuid":"0f3hPcKaTH7ABaG1hn4P$x","ifcClass":"IfcPlate","buildingId":"process_plant","buildingName":"Zona de separación de aire","sourceDocumentId":"LHD2609-JG00100-20260904","sourceRepresentationKind":"foundation"} | 2CD0F, 2CD5B, 2CD27, 2CDA3, 2CD1F, 2CD20, 2CD7E, 2CEC8, 2CEA3 | 0.18 | 0.2 | 0.16 | Contornos y sección documentados por el fabricante | found_0904_c9d35e22550ddd | 0.4 | 0.02 | M1: detalle20 mm; MJ1/MJ2:20 mm derivados del contorno lateral80 mm a escala4, no de una cota explícita. | C38 | Fz=-1500 | 25000.0 / 14600.0
Cimentación de soporte de tuberías C39 · placa embebida MJ-1 | 0.450753 | 0.450754 | 0.02 | 286.28 | 286.3 | 0.352 | 0.0032 | {"documentId":"LHD2609-JG00100-20260904","title":"Cimentaciones de equipos y pedestales del fabricante · revisión recibida 04/09/2026","date":"2026-09-04","sheet":"ZD1 / DZ-1","fileName":"LHD2609-JG00100_20260904.dwg","revisionCaveat":"Fecha de revisión tomada del nombre recibido; cajetines internos mantienen 02/07/2026 y algunos textos de plantilla.","sourceFileSha256":"b42eb027b7bc0b14c38d1d13514f4899b58a732aa8d0ba2ccf10fa2fc3192890"} | {"documented":[{"label":"Extensión local X","value":0.4,"unit":"m","source":"2CD10, 2CD5C, 2CD28, 2CDA4, 2CD1D, 2CD1E, 2CD7F, 2CEC9, 2CEA4","status":"derivada del contorno CAD"},{"label":"Extensión local Y","value":0.4,"unit":"m","source":"2CD10, 2CD5C, 2CD28, 2CDA4, 2CD1D, 2CD1E, 2CD7F, 2CEC9, 2CEA4","status":"derivada del contorno CAD"},{"label":"Cota inferior relativa adoptada","value":0.18000000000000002,"unit":"m","source":"ZD1 / DZ-1","status":"documentada"},{"label":"Cota superior relativa adoptada","value":0.2,"unit":"m","source":"ZD1 / DZ-1","status":"documentada / separación por material"}],"geometry":[{"label":"Extensión de la malla en X","value":0.45075299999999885,"unit":"m","source":"Geometría releída del IFC; datum absoluto de proceso provisional","status":"derivado"},{"label":"Extensión de la malla en Y","value":0.4507539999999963,"unit":"m","source":"Geometría releída del IFC; datum absoluto de proceso provisional","status":"derivado"},{"label":"Extensión de la malla en Z","value":0.020000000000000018,"unit":"m","source":"Geometría releída del IFC; datum absoluto de proceso provisional","status":"derivado"},{"label":"Cota inferior de visualización","value":286.28,"unit":"m","source":"Geometría releída del IFC; datum absoluto de proceso provisional","status":"derivado"},{"label":"Cota superior de visualización","value":286.3,"unit":"m","source":"Geometría releída del IFC; datum absoluto de proceso provisional","status":"derivado"}]} | [] | {"Cota inferior relativa (m)":0.18000000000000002,"Cota superior relativa (m)":0.2,"Cero absoluto de visualización (m)":286.1,"Estado del cero absoluto":"Provisional","Criterio":"Las cotas relativas proceden del dibujo; la equivalencia absoluta no está confirmada."} | SUP-C39 | [] | ["C39"] | ZD1 / DZ-1 | ["2CD10","2CD5C","2CD28","2CDA4","2CD1D","2CD1E","2CD7F","2CEC9","2CEA4"] | SUP-C39/Cimentación de soporte de tuberías C39 · placa embebida MJ-1 | {"boundingBoxM":{"min":[60.6163,40.63423,1.28],"max":[61.067053,41.084984,1.3]},"extentsM":[0.450753,0.450754,0.02],"meshSurfaceM2":0.352,"meshVolumeM3":0.0032,"closedSolid":true,"basis":"Magnitudes de las mallas representadas, no cantidades certificadas de obra, compra o fabricación. Las partes pueden compartir superficies; no se suman como un despiece de materiales."} | {"elementId":"found_0904_5d762f65bd7a08","ifcGuid":"3zYk_M29TIfAjDhxMrIr9H","ifcClass":"IfcPlate","buildingId":"process_plant","buildingName":"Zona de separación de aire","sourceDocumentId":"LHD2609-JG00100-20260904","sourceRepresentationKind":"foundation"} | 2CD10, 2CD5C, 2CD28, 2CDA4, 2CD1D, 2CD1E, 2CD7F, 2CEC9, 2CEA4 | 0.18 | 0.2 | 0.16 | Contornos y sección documentados por el fabricante | found_0904_5d762f65bd7a08 | 0.4 | 0.02 | M1: detalle20 mm; MJ1/MJ2:20 mm derivados del contorno lateral80 mm a escala4, no de una cota explícita. | C39 | Fz=-1500 | 26600.0 / 14600.0
Cimentación de soporte de tuberías C40 · placa embebida MJ-1 | 0.450754 | 0.450754 | 0.02 | 286.28 | 286.3 | 0.352 | 0.0032 | {"documentId":"LHD2609-JG00100-20260904","title":"Cimentaciones de equipos y pedestales del fabricante · revisión recibida 04/09/2026","date":"2026-09-04","sheet":"ZD1 / DZ-1","fileName":"LHD2609-JG00100_20260904.dwg","revisionCaveat":"Fecha de revisión tomada del nombre recibido; cajetines internos mantienen 02/07/2026 y algunos textos de plantilla.","sourceFileSha256":"b42eb027b7bc0b14c38d1d13514f4899b58a732aa8d0ba2ccf10fa2fc3192890"} | {"documented":[{"label":"Extensión local X","value":0.4,"unit":"m","source":"2CD11, 2CD5D, 2CD29, 2CDA5, 2CD1A, 2CD1B, 2CD80, 2CECA, 2CEA5","status":"derivada del contorno CAD"},{"label":"Extensión local Y","value":0.4,"unit":"m","source":"2CD11, 2CD5D, 2CD29, 2CDA5, 2CD1A, 2CD1B, 2CD80, 2CECA, 2CEA5","status":"derivada del contorno CAD"},{"label":"Cota inferior relativa adoptada","value":0.18000000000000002,"unit":"m","source":"ZD1 / DZ-1","status":"interpretación con conflicto conservado"},{"label":"Cota superior relativa adoptada","value":0.2,"unit":"m","source":"ZD1 / DZ-1","status":"documentada / separación por material"}],"geometry":[{"label":"Extensión de la malla en X","value":0.4507539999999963,"unit":"m","source":"Geometría releída del IFC; datum absoluto de proceso provisional","status":"derivado"},{"label":"Extensión de la malla en Y","value":0.45075400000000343,"unit":"m","source":"Geometría releída del IFC; datum absoluto de proceso provisional","status":"derivado"},{"label":"Extensión de la malla en Z","value":0.020000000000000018,"unit":"m","source":"Geometría releída del IFC; datum absoluto de proceso provisional","status":"derivado"},{"label":"Cota inferior de visualización","value":286.28,"unit":"m","source":"Geometría releída del IFC; datum absoluto de proceso provisional","status":"derivado"},{"label":"Cota superior de visualización","value":286.3,"unit":"m","source":"Geometría releída del IFC; datum absoluto de proceso provisional","status":"derivado"}]} | ["Identificador original HA-40 en columna de posición; C40 se infiere por secuencia. Se conserva el original y no se interpreta como material."] | {"Cota inferior relativa (m)":0.18000000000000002,"Cota superior relativa (m)":0.2,"Cero absoluto de visualización (m)":286.1,"Estado del cero absoluto":"Provisional","Criterio":"Las cotas relativas proceden del dibujo; la equivalencia absoluta no está confirmada."} | SUP-C40 | [] | ["C40"] | ZD1 / DZ-1 | ["2CD11","2CD5D","2CD29","2CDA5","2CD1A","2CD1B","2CD80","2CECA","2CEA5"] | SUP-C40/Cimentación de soporte de tuberías C40 · placa embebida MJ-1 | {"boundingBoxM":{"min":[58.622598,37.880114,1.28],"max":[59.073352,38.330868,1.3]},"extentsM":[0.450754,0.450754,0.02],"meshSurfaceM2":0.352,"meshVolumeM3":0.0032,"closedSolid":true,"basis":"Magnitudes de las mallas representadas, no cantidades certificadas de obra, compra o fabricación. Las partes pueden compartir superficies; no se suman como un despiece de materiales."} | {"elementId":"found_0904_e47e3b0a848d01","ifcGuid":"2hlTBvK$HS7Pq1r7EuRTtZ","ifcClass":"IfcPlate","buildingId":"process_plant","buildingName":"Zona de separación de aire","sourceDocumentId":"LHD2609-JG00100-20260904","sourceRepresentationKind":"foundation"} | 2CD11, 2CD5D, 2CD29, 2CDA5, 2CD1A, 2CD1B, 2CD80, 2CECA, 2CEA5 | 0.18 | 0.2 | 0.16 | Sección y contornos del fabricante; incidencias conservadas | found_0904_e47e3b0a848d01 | 0.4 | 0.02 | M1: detalle20 mm; MJ1/MJ2:20 mm derivados del contorno lateral80 mm a escala4, no de una cota explícita. | HA-40 | Fz=-1500 | 25000.0 / 11600.0 | JH_Trazabilidad - Incidencias de origen: Identificador original HA-40 en columna de posición; C40 se infiere por secuencia. Se conserva el original y no se interpreta como material.
Cimentación de soporte de tuberías C41 · placa embebida MJ-1 | 0.450754 | 0.450754 | 0.02 | 286.28 | 286.3 | 0.352 | 0.0032 | {"documentId":"LHD2609-JG00100-20260904","title":"Cimentaciones de equipos y pedestales del fabricante · revisión recibida 04/09/2026","date":"2026-09-04","sheet":"ZD1 / DZ-1","fileName":"LHD2609-JG00100_20260904.dwg","revisionCaveat":"Fecha de revisión tomada del nombre recibido; cajetines internos mantienen 02/07/2026 y algunos textos de plantilla.","sourceFileSha256":"b42eb027b7bc0b14c38d1d13514f4899b58a732aa8d0ba2ccf10fa2fc3192890"} | {"documented":[{"label":"Extensión local X","value":0.4,"unit":"m","source":"2CD2C, 2CD5E, 2CD2F, 2CDA6, 2CD2D, 2CD2E, 2CD81, 2CECB, 2CEA6","status":"derivada del contorno CAD"},{"label":"Extensión local Y","value":0.4,"unit":"m","source":"2CD2C, 2CD5E, 2CD2F, 2CDA6, 2CD2D, 2CD2E, 2CD81, 2CECB, 2CEA6","status":"derivada del contorno CAD"},{"label":"Cota inferior relativa adoptada","value":0.18000000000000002,"unit":"m","source":"ZD1 / DZ-1","status":"documentada"},{"label":"Cota superior relativa adoptada","value":0.2,"unit":"m","source":"ZD1 / DZ-1","status":"documentada / separación por material"}],"geometry":[{"label":"Extensión de la malla en X","value":0.45075400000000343,"unit":"m","source":"Geometría releída del IFC; datum absoluto de proceso provisional","status":"derivado"},{"label":"Extensión de la malla en Y","value":0.4507539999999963,"unit":"m","source":"Geometría releída del IFC; datum absoluto de proceso provisional","status":"derivado"},{"label":"Extensión de la malla en Z","value":0.020000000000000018,"unit":"m","source":"Geometría releída del IFC; datum absoluto de proceso provisional","status":"derivado"},{"label":"Cota inferior de visualización","value":286.28,"unit":"m","source":"Geometría releída del IFC; datum absoluto de proceso provisional","status":"derivado"},{"label":"Cota superior de visualización","value":286.3,"unit":"m","source":"Geometría releída del IFC; datum absoluto de proceso provisional","status":"derivado"}]} | [] | {"Cota inferior relativa (m)":0.18000000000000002,"Cota superior relativa (m)":0.2,"Cero absoluto de visualización (m)":286.1,"Estado del cero absoluto":"Provisional","Criterio":"Las cotas relativas proceden del dibujo; la equivalencia absoluta no está confirmada."} | SUP-C41 | [] | ["C41"] | ZD1 / DZ-1 | ["2CD2C","2CD5E","2CD2F","2CDA6","2CD2D","2CD2E","2CD81","2CECB","2CEA6"] | SUP-C41/Cimentación de soporte de tuberías C41 · placa embebida MJ-1 | {"boundingBoxM":{"min":[60.207688,37.662188,1.28],"max":[60.658442,38.112942,1.3]},"extentsM":[0.450754,0.450754,0.02],"meshSurfaceM2":0.352,"meshVolumeM3":0.0032,"closedSolid":true,"basis":"Magnitudes de las mallas representadas, no cantidades certificadas de obra, compra o fabricación. Las partes pueden compartir superficies; no se suman como un despiece de materiales."} | {"elementId":"found_0904_a2af6a0080a0c3","ifcGuid":"1a$3IU1AzOuxPH7r82BrPm","ifcClass":"IfcPlate","buildingId":"process_plant","buildingName":"Zona de separación de aire","sourceDocumentId":"LHD2609-JG00100-20260904","sourceRepresentationKind":"foundation"} | 2CD2C, 2CD5E, 2CD2F, 2CDA6, 2CD2D, 2CD2E, 2CD81, 2CECB, 2CEA6 | 0.18 | 0.2 | 0.16 | Contornos y sección documentados por el fabricante | found_0904_a2af6a0080a0c3 | 0.4 | 0.02 | M1: detalle20 mm; MJ1/MJ2:20 mm derivados del contorno lateral80 mm a escala4, no de una cota explícita. | C41 | Fz=-1500 | 26600.0 / 11600.0

# IfcRailing: Valla metálica de ensamblaje (6)
In: Parcela industrial Jinhong
Description: Modelo de coordinación a partir de planos. Las dimensiones documentadas se separan de las simplificaciones gráficas y cotas de terreno interpoladas; no son cantidades certificadas de obra.; PredefinedType: USERDEFINED; Document: Detalles del vallado perimetral · paquete emitido 31/07/2026; Ubicación de muros perimetrales · CAD original; Implantación y rasantes de la parcela; Group: BIM · Vallado perimetral
JH_InformacionBIM - buildingId: site; buildingName: Urbanización y parcela; level: Exterior · vallado perimetral; category: Valla metálica de ensamblaje; ifcClass: IfcRailing; status: derivado; source: {"documentId":"JH-U010-20260731","title":"Detalles del vallado perimetral · paquete emitido 31/07/2026","sheet":"U010 · página 11 del PDF original","date":"2026-07-10","issueDate":"2026-07-31","note":"Fecha del cajetín 10/07/2026; último paquete disponible de esta especialidad emitido 31/07/2026."}; planSource: {"documentId":"JH-U009-20260731","title":"Ubicación de muros perimetrales · CAD original","sheet":"U009 · página 10 del PDF original","date":"2026-07-10","issueDate":"2026-07-31"}; material: {"name":"Valla metálica de ensamblaje","status":"documentado","source":"U010 · detalle del vallado / acceso"}; appearance: {"profileId":"fence_metal","name":"Valla metálica · gris neutro","status":"criterio_visual","basis":"U010 indica valla de ensamblaje y tubo 35 × 2 mm. Color y protección superficial no confirmados; gris neutro de visualización."}; visualLayer: {"id":"fences","name":"Vallado perimetral","defaultVisible":true}; representationKind: geometria_derivada_de_planos; fenceBasis: Ejes y polígonos del CAD U009; alturas y materiales de U010. Las aberturas de acceso se mantienen libres.; terrainBasis: Apoyo coordinado con la superficie de urbanización ya representada; interpolación sobre sus triángulos, con proyección al borde próximo cuando el eje queda fuera. No constituye rasante de ejecución. Datum absoluto pendiente de confirmación.; positioning: {"Trazado":"Coordenadas originales del DWG, ETRS89 / UTM 29N, origen local 729400 / 4301550 m","Apoyo":"Apoyo coordinado con la superficie de urbanización ya representada; interpolación sobre sus triángulos, con proyección al borde próximo cuando el eje queda fuera. No constituye rasante de ejecución. Datum absoluto pendiente de confirmación."}; issues: ["U010 indica 286,10 m en el vértice noreste y U004 288,00 m. En el vértice noroeste U010 indica 286,65 y 285,65 m, frente a 285,70 m de U004. Se conservan las alturas relativas del detalle; las cotas absolutas requieren coordinación.","Las juntas, anclajes, armaduras, transición escalonada exacta y ejecución sobre pendientes no se consideran definidos por esta malla."]; quantityEligible: no
JH_Trazabilidad - Documento de origen: U009 / U010 · paquete 31/07/2026 · cajetín 10/07/2026; Capa BIM: Vallado perimetral; Aplicabilidad a mediciones: Geometría de coordinación; no usar como cantidades certificadas.; Categoria: Valla metálica de ensamblaje; ClaseIFC: IfcRailing; EstadoDeInformacion: derivado; DocumentoFuente: {"documentId":"JH-U010-20260731","title":"Detalles del vallado perimetral · paquete emitido 31/07/2026","sheet":"U010 · página 11 del PDF original","date":"2026-07-10","issueDate":"2026-07-31","note":"Fecha del cajetín 10/07/2026; último paquete disponible de esta especialidad emitido 31/07/2026."}; IncidenciasPendientes: ["U010 indica 286,10 m en el vértice noreste y U004 288,00 m. En el vértice noroeste U010 indica 286,65 y 285,65 m, frente a 285,70 m de U004. Se conservan las alturas relativas del detalle; las cotas absolutas requieren coordinación.","Las juntas, anclajes, armaduras, transición escalonada exacta y ejecución sobre pendientes no se consideran definidos por esta malla."]; UsoDeLasMagnitudes: Modelo de coordinación a partir de planos. Las dimensiones documentadas se separan de las simplificaciones gráficas y cotas de terreno interpoladas; no son cantidades certificadas de obra.
JH_CriterioDePosicion - PosicionYEstado: {"Trazado":"Coordenadas originales del DWG, ETRS89 / UTM 29N, origen local 729400 / 4301550 m","Apoyo":"Apoyo coordinado con la superficie de urbanización ya representada; interpolación sobre sus triángulos, con proyección al borde próximo cuando el eje queda fuera. No constituye rasante de ejecución. Datum absoluto pendiente de confirmación."}
JH_EvidenciaDeMaterial - name: Valla metálica de ensamblaje; status: documentado; source: U010 · detalle del vallado / acceso
JH_DimensionesDocumentadas - Altura total sobre el terreno local: 2.5 m; Módulo nominal entre postes: 2 m; Altura de panel: 2 m
JH_CapaBIM - IdentificadorCapa: fences; NombreCapa: Vallado perimetral; Funcion: Valla metálica de ensamblaje; VisibilidadInicial: yes
JH_Vallado - Criterio: Ejes y polígonos del CAD U009; alturas y materiales de U010. Las aberturas de acceso se mantienen libres.; PlanoDeImplantacion: {"documentId":"JH-U009-20260731","title":"Ubicación de muros perimetrales · CAD original","sheet":"U009 · página 10 del PDF original","date":"2026-07-10","issueDate":"2026-07-31"}; NivelDelTerreno: Apoyo coordinado con la superficie de urbanización ya representada; interpolación sobre sus triángulos, con proyección al borde próximo cuando el eje queda fuera. No constituye rasante de ejecución. Datum absoluto pendiente de confirmación.; Simplificaciones: [{"label":"Separación gráfica máxima entre barras verticales","value":0.2,"unit":"m"},{"label":"Espesor gráfico de hilos","value":0.006,"unit":"m"},{"label":"Perfil gráfico perimetral","value":0.025,"unit":"m"},{"label":"Estado de la retícula","value":"Simplificación de visualización; abertura, hilos y recubrimiento sin especificación confirmada","unit":""}]; IncluirEnMediciones: no
JH_AcabadoVisual - Perfil: fence_metal; Acabado: Valla metálica · gris neutro; ColorRGB: [0.43,0.48,0.49]; Rugosidad: 0.6; Metallicidad: 0.3; Estado: criterio_visual; Referencia: U010 indica valla de ensamblaje y tubo 35 × 2 mm. Color y protección superficial no confirmados; gris neutro de visualización.
Name | dimensions | classification | fenceSegmentId = Trazado CAD = Tramo | geometryMetrics | Identificador
Paneles de vallado · Norte | {"documented":[{"label":"Altura total sobre el terreno local","value":2.5,"unit":"m"},{"label":"Módulo nominal entre postes","value":2.0,"unit":"m"},{"label":"Altura de panel","value":2.0,"unit":"m"}],"assumed":[{"label":"Separación gráfica máxima entre barras verticales","value":0.2,"unit":"m"},{"label":"Espesor gráfico de hilos","value":0.006,"unit":"m"},{"label":"Perfil gráfico perimetral","value":0.025,"unit":"m"},{"label":"Estado de la retícula","value":"Simplificación de visualización; abertura, hilos y recubrimiento sin especificación confirmada","unit":""}],"geometry":[{"label":"Extensión representada X","value":136.653795,"unit":"m"},{"label":"Extensión representada Y","value":18.863006,"unit":"m"},{"label":"Extensión representada Z","value":4.288893,"unit":"m"}]} | {"layerId":"fences","layerName":"Vallado perimetral","function":"Paneles de vallado · Norte"} | FENCE-21B1A-1 | {"boundingBoxM":{"min":[0.593236,90.506381,1.181574],"max":[137.247031,109.369387,5.470467]},"extentsM":[136.653795,18.863006,4.288893],"meshSurfaceM2":65.788655,"meshVolumeM3":0.229405,"closedSolid":true,"basis":"Modelo de coordinación a partir de planos. Las dimensiones documentadas se separan de las simplificaciones gráficas y cotas de terreno interpoladas; no son cantidades certificadas de obra."} | FENCE-21B1A-1-MESH
Paneles de vallado · Este | {"documented":[{"label":"Altura total sobre el terreno local","value":2.5,"unit":"m"},{"label":"Módulo nominal entre postes","value":2.0,"unit":"m"},{"label":"Altura de panel","value":2.0,"unit":"m"}],"assumed":[{"label":"Separación gráfica máxima entre barras verticales","value":0.2,"unit":"m"},{"label":"Espesor gráfico de hilos","value":0.006,"unit":"m"},{"label":"Perfil gráfico perimetral","value":0.025,"unit":"m"},{"label":"Estado de la retícula","value":"Simplificación de visualización; abertura, hilos y recubrimiento sin especificación confirmada","unit":""}],"geometry":[{"label":"Extensión representada X","value":12.13467,"unit":"m"},{"label":"Extensión representada Y","value":87.857691,"unit":"m"},{"label":"Extensión representada Z","value":3.07391,"unit":"m"}]} | {"layerId":"fences","layerName":"Vallado perimetral","function":"Paneles de vallado · Este"} | FENCE-21B1A-2 | {"boundingBoxM":{"min":[125.123037,2.66278,2.396674],"max":[137.257707,90.520471,5.470584]},"extentsM":[12.13467,87.857691,3.07391],"meshSurfaceM2":41.679779,"meshVolumeM3":0.146554,"closedSolid":true,"basis":"Modelo de coordinación a partir de planos. Las dimensiones documentadas se separan de las simplificaciones gráficas y cotas de terreno interpoladas; no son cantidades certificadas de obra."} | FENCE-21B1A-2-MESH
Paneles de vallado · Retorno sureste | {"documented":[{"label":"Altura total sobre el terreno local","value":2.5,"unit":"m"},{"label":"Módulo nominal entre postes","value":2.0,"unit":"m"},{"label":"Altura de panel","value":2.0,"unit":"m"}],"assumed":[{"label":"Separación gráfica máxima entre barras verticales","value":0.2,"unit":"m"},{"label":"Espesor gráfico de hilos","value":0.006,"unit":"m"},{"label":"Perfil gráfico perimetral","value":0.025,"unit":"m"},{"label":"Estado de la retícula","value":"Simplificación de visualización; abertura, hilos y recubrimiento sin especificación confirmada","unit":""}],"geometry":[{"label":"Extensión representada X","value":1.985154,"unit":"m"},{"label":"Extensión representada Y","value":0.298307,"unit":"m"},{"label":"Extensión representada Z","value":2.065141,"unit":"m"}]} | {"layerId":"fences","layerName":"Vallado perimetral","function":"Paneles de vallado · Retorno sureste"} | FENCE-21B1A-3 | {"boundingBoxM":{"min":[123.152226,2.652087,2.356586],"max":[125.13738,2.950394,4.421727]},"extentsM":[1.985154,0.298307,2.065141],"meshSurfaceM2":0.979473,"meshVolumeM3":0.003365,"closedSolid":true,"basis":"Modelo de coordinación a partir de planos. Las dimensiones documentadas se separan de las simplificaciones gráficas y cotas de terreno interpoladas; no son cantidades certificadas de obra."} | FENCE-21B1A-3-MESH
Paneles de vallado · Sur | {"documented":[{"label":"Altura total sobre el terreno local","value":2.5,"unit":"m"},{"label":"Módulo nominal entre postes","value":2.0,"unit":"m"},{"label":"Altura de panel","value":2.0,"unit":"m"}],"assumed":[{"label":"Separación gráfica máxima entre barras verticales","value":0.2,"unit":"m"},{"label":"Espesor gráfico de hilos","value":0.006,"unit":"m"},{"label":"Perfil gráfico perimetral","value":0.025,"unit":"m"},{"label":"Estado de la retícula","value":"Simplificación de visualización; abertura, hilos y recubrimiento sin especificación confirmada","unit":""}],"geometry":[{"label":"Extensión representada X","value":115.550684,"unit":"m"},{"label":"Extensión representada Y","value":15.975914,"unit":"m"},{"label":"Extensión representada Z","value":3.145178,"unit":"m"}]} | {"layerId":"fences","layerName":"Vallado perimetral","function":"Paneles de vallado · Sur"} | FENCE-21B33-1 | {"boundingBoxM":{"min":[6.020365,3.144437,1.236431],"max":[121.571049,19.120351,4.381609]},"extentsM":[115.550684,15.975914,3.145178],"meshSurfaceM2":55.1879,"meshVolumeM3":0.193305,"closedSolid":true,"basis":"Modelo de coordinación a partir de planos. Las dimensiones documentadas se separan de las simplificaciones gráficas y cotas de terreno interpoladas; no son cantidades certificadas de obra."} | FENCE-21B33-1-MESH
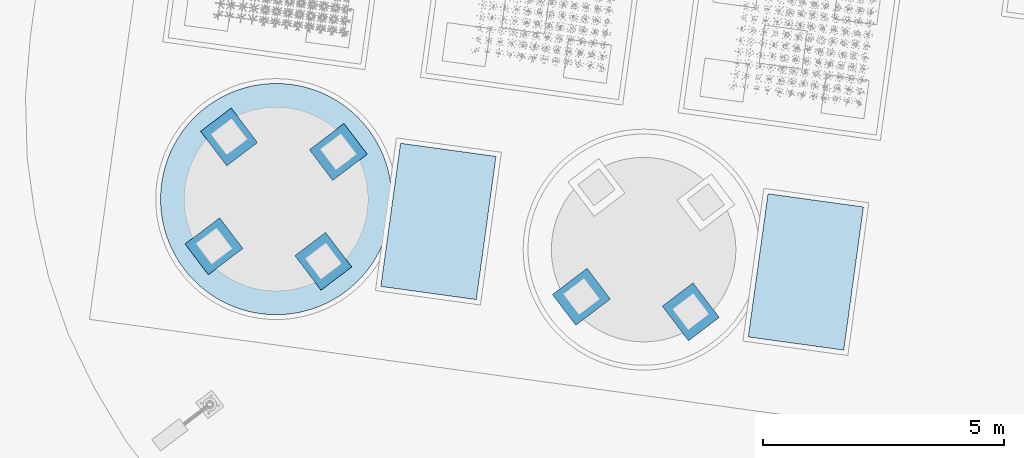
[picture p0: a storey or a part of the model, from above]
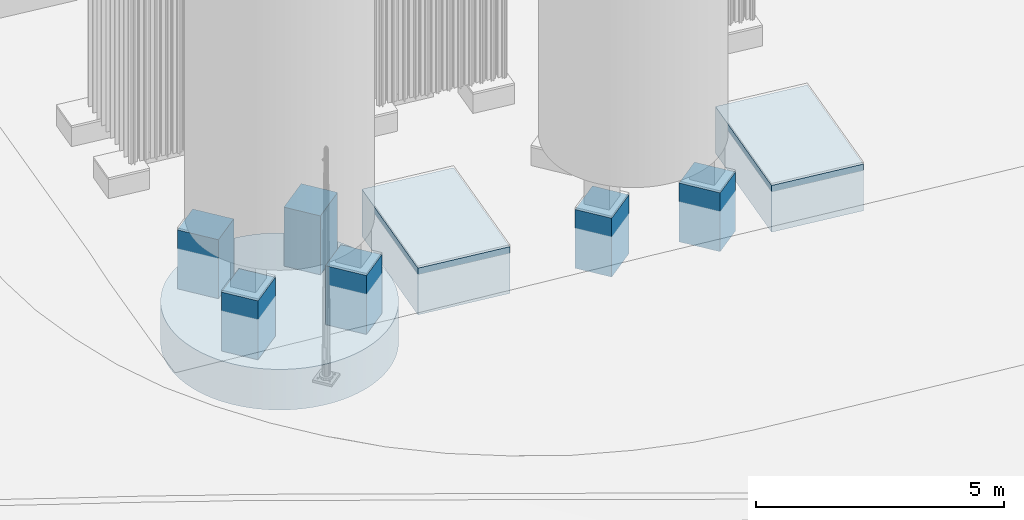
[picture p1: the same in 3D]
Properties of the parts of a building model (IFC4), part 101 of 134

# IfcRailing: Valla metálica de ensamblaje (6)
Name | dimensions | classification | fenceSegmentId = Trazado CAD = Tramo | geometryMetrics | Identificador
Paneles de vallado · Curva suroeste | {"documented":[{"label":"Altura total sobre el terreno local","value":2.5,"unit":"m"},{"label":"Módulo nominal entre postes","value":2.0,"unit":"m"},{"label":"Altura de panel","value":2.0,"unit":"m"}],"assumed":[{"label":"Separación gráfica máxima entre barras verticales","value":0.2,"unit":"m"},{"label":"Espesor gráfico de hilos","value":0.006,"unit":"m"},{"label":"Perfil gráfico perimetral","value":0.025,"unit":"m"},{"label":"Estado de la retícula","value":"Simplificación de visualización; abertura, hilos y recubrimiento sin especificación confirmada","unit":""}],"geometry":[{"label":"Extensión representada X","value":12.131548,"unit":"m"},{"label":"Extensión representada Y","value":17.839236,"unit":"m"},{"label":"Extensión representada Z","value":2.406132,"unit":"m"}]} | {"layerId":"fences","layerName":"Vallado perimetral","function":"Paneles de vallado · Curva suroeste"} | FENCE-21B33-2 | {"boundingBoxM":{"min":[-6.106145,19.095876,0.856898],"max":[6.025403,36.935112,3.26303]},"extentsM":[12.131548,17.839236,2.406132],"meshSurfaceM2":11.078155,"meshVolumeM3":0.039169,"closedSolid":true,"basis":"Modelo de coordinación a partir de planos. Las dimensiones documentadas se separan de las simplificaciones gráficas y cotas de terreno interpoladas; no son cantidades certificadas de obra."} | FENCE-21B33-2-MESH
Paneles de vallado · Oeste | {"documented":[{"label":"Altura total sobre el terreno local","value":2.5,"unit":"m"},{"label":"Módulo nominal entre postes","value":2.0,"unit":"m"},{"label":"Altura de panel","value":2.0,"unit":"m"}],"assumed":[{"label":"Separación gráfica máxima entre barras verticales","value":0.2,"unit":"m"},{"label":"Espesor gráfico de hilos","value":0.006,"unit":"m"},{"label":"Perfil gráfico perimetral","value":0.025,"unit":"m"},{"label":"Estado de la retícula","value":"Simplificación de visualización; abertura, hilos y recubrimiento sin especificación confirmada","unit":""}],"geometry":[{"label":"Extensión representada X","value":5.007776,"unit":"m"},{"label":"Extensión representada Y","value":56.487003,"unit":"m"},{"label":"Extensión representada Z","value":2.398982,"unit":"m"}]} | {"layerId":"fences","layerName":"Vallado perimetral","function":"Paneles de vallado · Oeste"} | FENCE-21B33-3 | {"boundingBoxM":{"min":[-5.796458,36.932161,0.857777],"max":[-0.788682,93.419164,3.256759]},"extentsM":[5.007776,56.487003,2.398982],"meshSurfaceM2":26.494825,"meshVolumeM3":0.093472,"closedSolid":true,"basis":"Modelo de coordinación a partir de planos. Las dimensiones documentadas se separan de las simplificaciones gráficas y cotas de terreno interpoladas; no son cantidades certificadas de obra."} | FENCE-21B33-3-MESH

# IfcRoof (2)
In: Planta baja
Description: Cubierta; Group: Arquitectura; BIM · Arquitectura
Pset_RoofCommon - IsExternal: yes
JH_InformacionBIM - level: Planta baja; category: Cubierta; ifcClass: IfcRoof; status: provisional; visualLayer: {"id":"architecture","name":"Arquitectura"}; componentSeparation: {"status":"objeto_independiente","note":"Control de visibilidad del objeto completo; la clasificación no altera la malla."}; classification: {"layerId":"architecture","layerName":"Arquitectura","role":"Cubierta","basis":"Clasificación por función del elemento; no modifica las especificaciones documentales."}; layerId: architecture
JH_Trazabilidad - Sistema de coordenadas: Coordenadas de proyecto en metros; sumar (729400, 4301550, 285) para recuperar las coordenadas UTM y cotas de los planos.; Uso del modelo: Reconstrucción tridimensional de la documentación y revisión preliminar de coordinación; pendiente de revisión por el equipo de diseño.; Verificación de la malla: Malla cerrada, orientación coherente de las caras y volumen positivo.; Referencia de implantación: Plano general U004 de 2026-07-31; geometría vectorial del PDF registrada con las coordenadas de lindero indicadas.; Disciplina: Arquitectura; Clase IFC: IfcRoof; Fase del modelo: V0.1 · Reconstrucción documental y coordinación preliminar; Representación geométrica: Sólido de malla triangular cerrada en IFC4; Aplicabilidad de las mediciones: Volumen exclusivamente geométrico; los espesores de representación, las simplificaciones y las envolventes no constituyen mediciones de compra, ejecución, fabricación ni volumen neto de material.; Capa BIM: Arquitectura; Estado del acabado: criterio_visual; Categoria: Cubierta; ClaseIFC: IfcRoof; EstadoDeInformacion: provisional; UsoDeLasMagnitudes: Geometría de coordinación. Los volúmenes de referencia y subcomponentes no son cantidades de material ni componentes de fabricación certificados.
JH_EvidenciaDeMaterial - status: known
JH_CapaBIM - IdentificadorCapa: architecture; NombreCapa: Arquitectura; Funcion: Cubierta; VisibilidadInicial: yes
JH_AcabadoVisual - Estado: criterio_visual; Referencia: Interpretación visual del material documental; el acabado, tono y parámetros PBR no son una especificación contractual.; Nota: La apariencia no certifica el material físico ni el acabado de fabricación.
Name | PredefinedType | Document | Material = JH_Trazabilidad, Material = name | Dimensiones de la caja local del elemento (X, Y, Z) | Cota mínima absoluta de la malla (m) | Cota máxima absoluta de la malla (m) | Volumen geométrico bruto (m3) = VolumenGeometrico (m3) = Volumen geométrico (m³) | Reference = Identificador del elemento = Identificador | ExtensionX (m) | ExtensionY (m) | ExtensionZ (m) | SuperficieDeLaMalla (m2) | buildingId | buildingName = Edificio | material | dimensions | JH_InformacionBIM, source = DocumentoFuente | issues = IncidenciasPendientes | positioning = PosicionYEstado | commonProperties | geometryMetrics | ifcAssociations | materialAppearance | visualizationIdentity | appearance | Planos de referencia | Base geométrica | Pendiente (%) = Pendiente | Estado de la implantación | Referencia del material = JH_EvidenciaDeMaterial, source | Cota de planta baja terminada (m) | Acabado de visualización = Acabado | Perfil | ColorRGB | Rugosidad | Metallicidad
Cubierta sándwich de la sala de bombas · 100 mm · pendiente 5 % | SHED_ROOF | Planos de arquitectura de la sala de bombas contra incendios; Planos de arquitectura de la sala de bombas contra incendios | Panel sándwich de acero con núcleo de lana de roca | 9.8 × 7.8 × 0.49 | 291.055 | 291.545 | 7.644 | pump_house_0039 | 10.7711 | 9.06211 | 0.49 | 156.591 | pump_house | Sala de bombas contra incendios | {"name":"Panel sándwich de acero con núcleo de lana de roca","source":"ARQ-SB-20260710 · Arquitectura A102 / p. 4, A103 / p. 5; Estructura A301 / p. 5; ARQ-OF-20260710 · A301 / p. 16, bloque correspondiente a la sala de bombas","status":"known"} | {"documented":[{"label":"Espesor del panel","value":0.1,"unit":"m","source":"ARQ-SB-20260710 · Arquitectura A102 / p. 4, A103 / p. 5; Estructura A301 / p. 5","status":"documentado"},{"label":"Pendiente","value":5,"unit":"%","source":"ARQ-SB-20260710 · Arquitectura A102 / p. 4, A103 / p. 5; Estructura A301 / p. 5","status":"documentado"}],"geometry":[{"label":"Dimensiones de la caja local del elemento (X, Y, Z)","value":"9.8 × 7.8 × 0.49","unit":"m","source":"Malla triangulada del elemento en ejes locales del edificio","status":"derivado"},{"label":"Cota mínima absoluta de la malla","value":291.055,"unit":"m","source":"Malla de proyecto y origen altimétrico 285 m","status":"derivado"},{"label":"Cota máxima absoluta de la malla","value":291.545,"unit":"m","source":"Malla de proyecto y origen altimétrico 285 m","status":"derivado"},{"label":"Volumen geométrico bruto","value":7.644,"unit":"m³","source":"Malla cerrada del elemento","status":"derivado"}],"notes":["Las dimensiones documentadas proceden de anotaciones o cuadros; la caja y el volumen se calculan a partir de la malla.","El volumen es exclusivamente geométrico y bruto; no representa una medición neta de material ni una cantidad de compra."]} | {"documentId":"ARQ-SB-20260710","title":"Planos de arquitectura de la sala de bombas contra incendios","date":"2026-07-10","sheet":"Arquitectura A102 / p. 4, A103 / p. 5; Estructura A301 / p. 5"} | ["Lado A: cabeza de pilar +5,00 m, correa de 0,20 m y panel de 0,10 m; encuentros de vigas y correas pendientes de revisión.","Registro de líneas del PDF general con envolvente de 10,2 × 8,2 m. Estimación de trabajo de implantación de ±0,15 m, pendiente de CAD nativo; no constituye una precisión topográfica garantizada."] | {"horizontalStatus":"derivado","verticalStatus":"provisional","baseElevationM":286.25,"note":"Registro de líneas del PDF general con envolvente de 10,2 × 8,2 m. Estimación de trabajo de implantación de ±0,15 m, pendiente de CAD nativo; no constituye una precisión topográfica garantizada."} | {"Pset_RoofCommon":{"IsExternal":{"value":true,"source":"ARQ-SB-20260710 · A101, A103 y alzados; elemento de la envolvente exterior identificada en planta","status":"known"}}} | {"boundingBoxM":{"min":[8.341469,25.629946,6.055],"max":[19.112531,34.692054,6.545]},"extentsM":[10.771062,9.062108,0.49],"meshSurfaceM2":156.590969,"meshVolumeM3":7.643999,"closedSolid":true,"basis":"Geometría triangulada releída del IFC; envolventes y magnitudes no contractuales."} | {"material":true,"document":true,"quantities":true,"containerGuid":"0Wh59pm9LO_einrwiq6Es1","containerName":"Planta baja"} | {"profileId":"sandwich_panel","name":"Panel sándwich · chapa gris clara","materialName":"Panel sándwich de acero con núcleo de lana de roca","physicalMaterialStatus":"known","physicalMaterialSource":"ARQ-SB-20260710 · Arquitectura A102 / p. 4, A103 / p. 5; Estructura A301 / p. 5; ARQ-OF-20260710 · A301 / p. 16, bloque correspondiente a la sala de bombas","appearanceStatus":"criterio_visual","appearanceBasis":"Interpretación visual del material documental; el acabado, tono y parámetros PBR no son una especificación contractual.","note":"La apariencia gráfica no modifica ni confirma la especificación física del material."} | {"elementId":"pump_house_0039","ifcGuid":"1HL6JXm2DQ2xWloeWDBP0b","ifcClass":"IfcRoof","buildingId":"pump_house","buildingName":"Sala de bombas contra incendios","sourceDocumentId":"ARQ-SB-20260710","sourceRepresentationKind":"documentary_mesh"} | {"profileId":"sandwich_panel","name":"Panel sándwich · chapa gris clara","status":"criterio_visual","basis":"Interpretación visual del material documental; el acabado, tono y parámetros PBR no son una especificación contractual.","physicalMaterialUnchanged":true} | ARQ-SB-20260710 · Arquitectura A102 / p. 4, A103 / p. 5; Estructura A301 / p. 5 | Pendiente y espesor documentados; cota del panel deducida de la cabeza de viga y las correas Z200, pendiente de comprobar los encuentros. | 5 | Registro de líneas del PDF general con envolvente de 10,2 × 8,2 m. Estimación de trabajo de implantación de ±0,15 m, pendiente de CAD nativo; no constituye una precisión topográfica garantizada. | ARQ-SB-20260710 · Arquitectura A102 / p. 4, A103 / p. 5; Estructura A301 / p. 5; ARQ-OF-20260710 · A301 / p. 16, bloque correspondiente a la sala de bombas | 286.25 | Panel sándwich · chapa gris clara | sandwich_panel | [0.85098,0.87451,0.87451] | 0.48 | 0.28 | JH_Trazabilidad - Espesor del panel (m): 0.1; Deducción de la cota: Lado A: cabeza de pilar +5,00 m, correa de 0,20 m y panel de 0,10 m; encuentros de vigas y correas pendientes de revisión.; JH_DimensionesDocumentadas - Espesor del panel: 0.1 m
Aislamiento e impermeabilización de cubierta de oficinas · envolvente | FLAT_ROOF | Planos de arquitectura del edificio de oficinas; Planos de arquitectura del edificio de oficinas | Formación de pendientes, lana de roca y lámina SBS | 19.6 × 9.6 × 0.1035 | 290.4 | 290.503 | 19.4746 | office_0212 | 12.1801 | 20.7249 | 0.1035 | 382.364 | office | Edificio de oficinas | {"name":"Formación de pendientes, lana de roca y lámina SBS","source":"ARQ-OF-20260710 · Arquitectura A106 / p. 8, A301 / p. 16","status":"known"} | {"documented":[{"label":"Pendiente","value":2,"unit":"%","source":"ARQ-OF-20260710 · Arquitectura A106 / p. 8, A301 / p. 16","status":"documentado"}],"geometry":[{"label":"Dimensiones de la caja local del elemento (X, Y, Z)","value":"19.6 × 9.6 × 0.1035","unit":"m","source":"Malla triangulada del elemento en ejes locales del edificio","status":"derivado"},{"label":"Cota mínima absoluta de la malla","value":290.4,"unit":"m","source":"Malla de proyecto y origen altimétrico 285 m","status":"derivado"},{"label":"Cota máxima absoluta de la malla","value":290.5035,"unit":"m","source":"Malla de proyecto y origen altimétrico 285 m","status":"derivado"},{"label":"Volumen geométrico bruto","value":19.47456,"unit":"m³","source":"Malla cerrada del elemento","status":"derivado"}],"notes":["Las dimensiones documentadas proceden de anotaciones o cuadros; la caja y el volumen se calculan a partir de la malla.","El volumen es exclusivamente geométrico y bruto; no representa una medición neta de material ni una cantidad de compra."]} | {"documentId":"ARQ-OF-20260710","title":"Planos de arquitectura del edificio de oficinas","date":"2026-07-10","sheet":"Arquitectura A106 / p. 8, A301 / p. 16"} | ["El plano general de 2026-07-31 mantiene el edificio de oficinas de 200 m², mientras documentación anterior indica su supresión. Se conserva lo dibujado, pendiente de confirmación de la propiedad y del equipo de diseño.","Representación con espesor medio de la composición; espesor detallado del mortero no especificado. No define cotas de fabricación de los desagües.","Registro de líneas del PDF general, envolvente de 20 × 10 m; eje local 1 al norte y acceso del lado A al oeste. Estimación de trabajo de implantación de ±0,15 m, pendiente de CAD; no constituye una precisión topográfica garantizada."] | {"horizontalStatus":"derivado","verticalStatus":"provisional","baseElevationM":285.95,"note":"Registro de líneas del PDF general, envolvente de 20 × 10 m; eje local 1 al norte y acceso del lado A al oeste. Estimación de trabajo de implantación de ±0,15 m, pendiente de CAD; no constituye una precisión topográfica garantizada."} | {"Pset_RoofCommon":{"IsExternal":{"value":true,"source":"ARQ-OF-20260710 · A101, A103 y alzados; elemento de la envolvente exterior identificada en planta","status":"known"}}} | {"boundingBoxM":{"min":[15.043934,71.967549,5.4],"max":[27.224066,92.692451,5.5035]},"extentsM":[12.180132,20.724902,0.1035],"meshSurfaceM2":382.364365,"meshVolumeM3":19.474558,"closedSolid":true,"basis":"Geometría triangulada releída del IFC; envolventes y magnitudes no contractuales."} | {"material":true,"document":true,"quantities":true,"containerGuid":"3ztlotcerHPueDgxP84R6z","containerName":"Planta baja"} | {"profileId":"roof_membrane","name":"Cubierta impermeabilizada · gris oscuro","materialName":"Formación de pendientes, lana de roca y lámina SBS","physicalMaterialStatus":"known","physicalMaterialSource":"ARQ-OF-20260710 · Arquitectura A106 / p. 8, A301 / p. 16","appearanceStatus":"criterio_visual","appearanceBasis":"Interpretación visual del material documental; el acabado, tono y parámetros PBR no son una especificación contractual.","note":"La apariencia gráfica no modifica ni confirma la especificación física del material."} | {"elementId":"office_0212","ifcGuid":"3k4mWZ_pvJZRvWJ1uND1mv","ifcClass":"IfcRoof","buildingId":"office","buildingName":"Edificio de oficinas","sourceDocumentId":"ARQ-OF-20260710","sourceRepresentationKind":"documentary_mesh"} | {"profileId":"roof_membrane","name":"Cubierta impermeabilizada · gris oscuro","status":"criterio_visual","basis":"Interpretación visual del material documental; el acabado, tono y parámetros PBR no son una especificación contractual.","physicalMaterialUnchanged":true} | ARQ-OF-20260710 · Arquitectura A106 / p. 8, A301 / p. 16 | Formación de pendientes de 50 mm medios, lana de roca de 50 mm y SBS de 3,5 mm; la pendiente del 2 % no se ha modelado geométricamente. | 2 | Registro de líneas del PDF general, envolvente de 20 × 10 m; eje local 1 al norte y acceso del lado A al oeste. Estimación de trabajo de implantación de ±0,15 m, pendiente de CAD; no constituye una precisión topográfica garantizada. | ARQ-OF-20260710 · Arquitectura A106 / p. 8, A301 / p. 16 | 285.95 | Cubierta impermeabilizada · gris oscuro | roof_membrane | [0.4,0.423529,0.427451] | 0.96 | 0 | JH_Trazabilidad - Observaciones: Representación con espesor medio de la composición; espesor detallado del mortero no especificado. No define cotas de fabricación de los desagües.; Discrepancia entre versiones: El plano general de 2026-07-31 mantiene el edificio de oficinas de 200 m², mientras documentación anterior indica su supresión. Se conserva lo dibujado, pendiente de confirmación de la propiedad y del equipo de diseño.

# IfcSlab (5)
JH_InformacionBIM - ifcClass: IfcSlab; componentSeparation: {"status":"objeto_independiente","note":"Control de visibilidad del objeto completo; la clasificación no altera la malla."}
JH_Trazabilidad - Clase IFC: IfcSlab; ClaseIFC: IfcSlab; UsoDeLasMagnitudes: Geometría de coordinación. Los volúmenes de referencia y subcomponentes no son cantidades de material ni componentes de fabricación certificados.
JH_CapaBIM - VisibilidadInicial: yes
JH_AcabadoVisual - Metallicidad: 0; Nota: La apariencia no certifica el material físico ni el acabado de fabricación.
Name | In | Description = category = Categoria = Funcion | PredefinedType | Document | Reference = Identificador | ExtensionX (m) | ExtensionY (m) | ExtensionZ (m) | SuperficieDeLaMalla (m2) | VolumenGeometrico (m3) | buildingId | buildingName | level | material | dimensions | JH_InformacionBIM, source = DocumentoFuente | JH_InformacionBIM, status = EstadoDeInformacion | positioning = PosicionYEstado | issues = IncidenciasPendientes | geometryMetrics | ifcAssociations | visualLayer | materialAppearance | visualizationIdentity | classification | layerId = IdentificadorCapa | appearance | Disciplina | Fase del modelo | JH_Trazabilidad, Material = name | Capa BIM = NombreCapa | Acabado de visualización = Acabado | Estado del acabado = Estado | JH_EvidenciaDeMaterial, source | JH_EvidenciaDeMaterial, status | Perfil | ColorRGB | Rugosidad | Referencia | Group | Material | Dimensiones de la caja local del elemento (X, Y, Z) | Cota mínima absoluta de la malla (m) | Cota máxima absoluta de la malla (m) | Volumen geométrico bruto (m3) = GrossVolume (m3) = Volumen geométrico (m³) | Planos de referencia = Referencia del material | Edificio | Base geométrica | Sistema de coordenadas | Uso del modelo | Verificación de la malla | Referencia de implantación | Estado de la implantación | Identificador del elemento | Representación geométrica | Aplicabilidad de las mediciones | Cota de planta baja terminada (m) | Discrepancia entre versiones
Plataforma de equipos 01 · cota provisional | Parcela industrial Jinhong | Plataforma de equipos | BASESLAB | Planos de urbanización y ordenación general de Jinhong | site_003 | 34.5147 | 60.063 | 0.15 | 3096.31 | 230.336 | site | Urbanización y parcela | Plataforma exterior · cota provisional 286,10 m | {"name":"No especificado","source":"Sin especificación de material en la documentación revisada","status":"unknown"} | {"documented":[{"label":"Anchura acotada de la plataforma","value":27,"unit":"m","source":"URB-20260731 · U004","status":"documentado"},{"label":"Longitud acotada de la plataforma","value":57,"unit":"m","source":"URB-20260731 · U004","status":"documentado"}],"geometry":[{"label":"Extensión de la malla en X","value":34.514707,"unit":"m","source":"Calculada a partir de los vértices del modelo","status":"derivado"},{"label":"Extensión de la malla en Y","value":60.063012,"unit":"m","source":"Calculada a partir de los vértices del modelo","status":"derivado"},{"label":"Extensión de la malla en Z","value":0.15,"unit":"m","source":"Calculada a partir de los vértices del modelo","status":"derivado"},{"label":"Cota inferior del modelo","value":285.95,"unit":"m","source":"Coordenada Z mínima de la malla más origen vertical de 285 m","status":"derivado"},{"label":"Cota superior del modelo","value":286.1,"unit":"m","source":"Coordenada Z máxima de la malla más origen vertical de 285 m","status":"derivado"},{"label":"Superficie proyectada en planta extraída del PDF","value":1535.57,"unit":"m²","source":"URB-20260731 · U004 · triangulación del relleno","status":"derivado"},{"label":"Espesor de visualización adoptado","value":0.15,"unit":"m","source":"Convención de visualización del modelo","status":"provisional"}],"notes":["Las extensiones de la malla se miden en los ejes del proyecto tras el giro de implantación; no sustituyen las dimensiones locales del fabricante.","La envolvente, su volumen y los espesores de visualización no son volúmenes de material ni cantidades de compra, construcción o fabricación.","La superficie derivada del relleno del PDF, 1 535,57 m², puede diferir de 27 × 57 m por tolerancias de extracción y registro; no es una medición contractual.","Las dimensiones documentadas distinguen cotas explícitas y medidas extraídas de contornos CAD; las dimensiones geométricas describen únicamente la malla publicada."]} | {"documentId":"URB-20260731","title":"Planos de urbanización y ordenación general de Jinhong","sheet":"U004 · página 5","date":"2026-07-31"} | provisional | {"horizontalStatus":"derivado","verticalStatus":"provisional","baseElevationM":285.95,"note":"Plano horizontal provisional a cota 286,10 m, tomada del vial próximo. Pendiente de confirmar con la explanación y el datum del fabricante."} | ["Espesor supuesto exclusivamente para visualizar la superficie; material, composición y espesor constructivo sin especificar.","Base común provisional a cota 286,10 m tomada del vial próximo. Falta coordinar la cota de las cimentaciones y la superficie real de montaje."] | {"boundingBoxM":{"min":[32.501005,26.339843,0.95],"max":[67.015712,86.402855,1.1]},"extentsM":[34.514707,60.063012,0.15],"meshSurfaceM2":3096.31394,"meshVolumeM3":230.335556,"closedSolid":true,"basis":"Geometría triangulada releída del IFC; envolventes y magnitudes no contractuales."} | {"material":false,"document":true,"quantities":true,"containerGuid":"17utmjd_LKsAVvPyuSUhFt","containerName":"Parcela industrial Jinhong"} | {"id":"site","name":"Urbanización"} | {"profileId":"exterior_concrete","name":"Pavimento exterior · hormigón provisional","materialName":"No especificado","physicalMaterialStatus":"unknown","physicalMaterialSource":"Sin especificación de material en la documentación revisada","appearanceStatus":"provisional","appearanceBasis":"Criterio visual autorizado para plataformas y pavimentos; material y sección constructiva pendientes.","note":"La apariencia gráfica no modifica ni confirma la especificación física del material."} | {"elementId":"site_003","ifcGuid":"1VzHenHPPIWAonoVm8KFpS","ifcClass":"IfcSlab","buildingId":"site","buildingName":"Urbanización y parcela","sourceDocumentId":"URB-20260731","sourceRepresentationKind":"documentary_mesh"} | {"layerId":"site","layerName":"Urbanización","role":"Plataforma de equipos","basis":"Clasificación por función del elemento; no modifica las especificaciones documentales."} | site | {"profileId":"exterior_concrete","name":"Pavimento exterior · hormigón provisional","status":"provisional","basis":"Criterio visual autorizado para plataformas y pavimentos; material y sección constructiva pendientes.","physicalMaterialUnchanged":true} | Urbanización | V0.1 · Reconstrucción a partir de planos y coordinación preliminar | No especificado | Urbanización | Pavimento exterior · hormigón provisional | provisional | Sin especificación de material en la documentación revisada | unknown | exterior_concrete | [0.698039,0.690196,0.647059] | 0.94 | Criterio visual autorizado para plataformas y pavimentos; material y sección constructiva pendientes. | Urbanización; BIM · Urbanización | JH_DimensionesDelModelo - Extensión de la malla en X: 34.5147 m; Extensión de la malla en Y: 60.063 m; Extensión de la malla en Z: 0.15 m; Cota inferior del modelo: 285.95 m; Cota superior del modelo: 286.1 m; Superficie proyectada en planta extraída del PDF: 1535.57 m2; Espesor de visualización adoptado: 0.15 m; JH_Trazabilidad - Documento de origen: Planos de urbanización y ordenación general de Jinhong · 2026-07-31 · U004 · página 5; Lámina de origen: U004 · página 5 del PDF; Geometría en planta: Triángulos de relleno originales del PDF, registrados mediante puntos de control UTM; contorno extraído de la documentación.; Superficie proyectada en planta (m²): 1535.57; Estado de las cotas: Plano horizontal provisional a cota 286,10 m, tomada del vial próximo. Pendiente de confirmar con la explanación y el datum del fabricante.; Espesor de visualización (m): 0.15; Estado del espesor: Espesor supuesto exclusivamente para visualización; no utilizable en mediciones.; Estado del modelo: Coordinación preliminar; pendiente de revisión.; Identificador del objeto: site_003; Representación geométrica IFC: Sólido IFC4 mediante malla triangular cerrada; Aplicabilidad a mediciones: Los equipos se representan mediante envolventes. Los espesores y alturas supuestos y el volumen de las envolventes no representan cantidades de materiales, compras, construcción o fabricación.; Estado de la información: provisional; JH_DimensionesDocumentadas - Anchura acotada de la plataforma: 27 m; Longitud acotada de la plataforma: 57 m
Solera de hormigón armado de la sala de bombas · espesor pendiente | Planta baja | Losa | BASESLAB | Planos de arquitectura de la sala de bombas contra incendios | pump_house_0001 | 11.2218 | 9.51286 | 0.3 | 178.32 | 25.092 | pump_house | Sala de bombas contra incendios | Planta baja | {"name":"Hormigón armado","source":"ARQ-SB-20260710 · Arquitectura A201 / p. 13; Cuadro de materiales A301 (arquitectura de oficinas, p. 16)","status":"known"} | {"documented":[{"label":"Espesor","value":0.3,"unit":"m","source":"ARQ-SB-20260710 · Arquitectura A201 / p. 13; Cuadro de materiales A301 (arquitectura de oficinas, p. 16)","status":"provisional"}],"geometry":[{"label":"Dimensiones de la caja local del elemento (X, Y, Z)","value":"10.2 × 8.2 × 0.3","unit":"m","source":"Malla triangulada del elemento en ejes locales del edificio","status":"derivado"},{"label":"Cota mínima absoluta de la malla","value":285.95,"unit":"m","source":"Malla de proyecto y origen altimétrico 285 m","status":"derivado"},{"label":"Cota máxima absoluta de la malla","value":286.25,"unit":"m","source":"Malla de proyecto y origen altimétrico 285 m","status":"derivado"},{"label":"Volumen geométrico bruto","value":25.092,"unit":"m³","source":"Malla cerrada del elemento","status":"derivado"}],"notes":["Las dimensiones documentadas proceden de anotaciones o cuadros; la caja y el volumen se calculan a partir de la malla.","El volumen es exclusivamente geométrico y bruto; no representa una medición neta de material ni una cantidad de compra."]} | {"documentId":"ARQ-SB-20260710","title":"Planos de arquitectura de la sala de bombas contra incendios","date":"2026-07-10","sheet":"Arquitectura A201 / p. 13; Cuadro de materiales A301 (arquitectura de oficinas, p. 16)"} | provisional | {"horizontalStatus":"derivado","verticalStatus":"provisional","baseElevationM":286.25,"note":"Registro de líneas del PDF general con envolvente de 10,2 × 8,2 m. Estimación de trabajo de implantación de ±0,15 m, pendiente de CAD nativo; no constituye una precisión topográfica garantizada."} | ["A201 indica 300 mm de C25 sobre 100 mm de limpieza; el cuadro de materiales indica 200 mm de HA-25 sobre 80 mm de limpieza. El cajetín de A201 conserva una referencia a YUNENG ajena a este proyecto.","Clase de hormigón no unificada entre los documentos.","Registro de líneas del PDF general con envolvente de 10,2 × 8,2 m. Estimación de trabajo de implantación de ±0,15 m, pendiente de CAD nativo; no constituye una precisión topográfica garantizada."] | {"boundingBoxM":{"min":[8.116092,25.404569,0.95],"max":[19.337908,34.917431,1.25]},"extentsM":[11.221816,9.512862,0.3],"meshSurfaceM2":178.319978,"meshVolumeM3":25.091997,"closedSolid":true,"basis":"Geometría triangulada releída del IFC; envolventes y magnitudes no contractuales."} | {"material":true,"document":true,"quantities":true,"containerGuid":"0Wh59pm9LO_einrwiq6Es1","containerName":"Planta baja"} | {"id":"structure","name":"Estructura"} | {"profileId":"concrete_reinforced","name":"Hormigón armado · gris natural","materialName":"Hormigón armado","physicalMaterialStatus":"known","physicalMaterialSource":"ARQ-SB-20260710 · Arquitectura A201 / p. 13; Cuadro de materiales A301 (arquitectura de oficinas, p. 16)","appearanceStatus":"criterio_visual","appearanceBasis":"Interpretación visual del material documental; el acabado, tono y parámetros PBR no son una especificación contractual.","note":"La apariencia gráfica no modifica ni confirma la especificación física del material."} | {"elementId":"pump_house_0001","ifcGuid":"13oxqC799MmPQtcFiucqtb","ifcClass":"IfcSlab","buildingId":"pump_house","buildingName":"Sala de bombas contra incendios","sourceDocumentId":"ARQ-SB-20260710","sourceRepresentationKind":"documentary_mesh"} | {"layerId":"structure","layerName":"Estructura","role":"Losa","basis":"Clasificación por función del elemento; no modifica las especificaciones documentales."} | structure | {"profileId":"concrete_reinforced","name":"Hormigón armado · gris natural","status":"criterio_visual","basis":"Interpretación visual del material documental; el acabado, tono y parámetros PBR no son una especificación contractual.","physicalMaterialUnchanged":true} | Arquitectura | V0.1 · Reconstrucción documental y coordinación preliminar | Hormigón armado | Estructura | Hormigón armado · gris natural | criterio_visual | ARQ-SB-20260710 · Arquitectura A201 / p. 13; Cuadro de materiales A301 (arquitectura de oficinas, p. 16) | known | concrete_reinforced | [0.666667,0.662745,0.619608] | 0.96 | Interpretación visual del material documental; el acabado, tono y parámetros PBR no son una especificación contractual. | Arquitectura; BIM · Estructura | Hormigón armado | 10.2 × 8.2 × 0.3 | 285.95 | 286.25 | 25.092 | ARQ-SB-20260710 · Arquitectura A201 / p. 13; Cuadro de materiales A301 (arquitectura de oficinas, p. 16) | Sala de bombas contra incendios | Planta documentada; se adoptan 300 mm según A201, mientras otro cuadro indica 200 mm. Espesor pendiente de conciliación. | Coordenadas de proyecto en metros; sumar (729400, 4301550, 285) para recuperar las coordenadas UTM y cotas de los planos. | Reconstrucción tridimensional de la documentación y revisión preliminar de coordinación; pendiente de revisión por el equipo de diseño. | Malla cerrada, orientación coherente de las caras y volumen positivo. | Plano general U004 de 2026-07-31; geometría vectorial del PDF registrada con las coordenadas de lindero indicadas. | Registro de líneas del PDF general con envolvente de 10,2 × 8,2 m. Estimación de trabajo de implantación de ±0,15 m, pendiente de CAD nativo; no constituye una precisión topográfica garantizada. | pump_house_0001 | Sólido de malla triangular cerrada en IFC4 | Volumen exclusivamente geométrico; los espesores de representación, las simplificaciones y las envolventes no constituyen mediciones de compra, ejecución, fabricación ni volumen neto de material. | 286.25 | JH_Trazabilidad - Espesor (m): 0.3; Discrepancia pendiente: A201 indica 300 mm de C25 sobre 100 mm de limpieza; el cuadro de materiales indica 200 mm de HA-25 sobre 80 mm de limpieza. El cajetín de A201 conserva una referencia a YUNENG ajena a este proyecto.; JH_DimensionesDocumentadas - Espesor: 0.3 m
Losa inferior de hormigón armado de oficinas · 200 mm | Planta baja | Losa | BASESLAB | Planos de arquitectura del edificio de oficinas; Planos de arquitectura del edificio de oficinas | office_0207 | 12.6309 | 21.1757 | 0.2 | 412 | 40 | office | Edificio de oficinas | Planta baja | {"name":"Hormigón armado","source":"ARQ-OF-20260710 · Arquitectura A202 / p. 13, A301 / p. 16","status":"known"} | {"documented":[],"geometry":[{"label":"Dimensiones de la caja local del elemento (X, Y, Z)","value":"20 × 10 × 0.2","unit":"m","source":"Malla triangulada del elemento en ejes locales del edificio","status":"derivado"},{"label":"Cota mínima absoluta de la malla","value":285.11,"unit":"m","source":"Malla de proyecto y origen altimétrico 285 m","status":"derivado"},{"label":"Cota máxima absoluta de la malla","value":285.31,"unit":"m","source":"Malla de proyecto y origen altimétrico 285 m","status":"derivado"},{"label":"Volumen geométrico bruto","value":40.0,"unit":"m³","source":"Malla cerrada del elemento","status":"derivado"}],"notes":["Las dimensiones documentadas proceden de anotaciones o cuadros; la caja y el volumen se calculan a partir de la malla.","El volumen es exclusivamente geométrico y bruto; no representa una medición neta de material ni una cantidad de compra."]} | {"documentId":"ARQ-OF-20260710","title":"Planos de arquitectura del edificio de oficinas","date":"2026-07-10","sheet":"Arquitectura A202 / p. 13, A301 / p. 16"} | derivado | {"horizontalStatus":"derivado","verticalStatus":"derivado","baseElevationM":285.95,"note":"Registro de líneas del PDF general, envolvente de 20 × 10 m; eje local 1 al norte y acceso del lado A al oeste. Estimación de trabajo de implantación de ±0,15 m, pendiente de CAD; no constituye una precisión topográfica garantizada."} | ["El plano general de 2026-07-31 mantiene el edificio de oficinas de 200 m², mientras documentación anterior indica su supresión. Se conserva lo dibujado, pendiente de confirmación de la propiedad y del equipo de diseño.","Cámara ventilada de 500 mm conservada como vacío; casetones y armaduras no modelados.","Clase de hormigón de esta losa no especificada en el dato extraído.","Registro de líneas del PDF general, envolvente de 20 × 10 m; eje local 1 al norte y acceso del lado A al oeste. Estimación de trabajo de implantación de ±0,15 m, pendiente de CAD; no constituye una precisión topográfica garantizada."] | {"boundingBoxM":{"min":[14.818557,71.742172,0.11],"max":[27.449443,92.917828,0.31]},"extentsM":[12.630886,21.175656,0.2],"meshSurfaceM2":412.0,"meshVolumeM3":40.0,"closedSolid":true,"basis":"Geometría triangulada releída del IFC; envolventes y magnitudes no contractuales."} | {"material":true,"document":true,"quantities":true,"containerGuid":"3ztlotcerHPueDgxP84R6z","containerName":"Planta baja"} | {"id":"structure","name":"Estructura"} | {"profileId":"concrete_reinforced","name":"Hormigón armado · gris natural","materialName":"Hormigón armado","physicalMaterialStatus":"known","physicalMaterialSource":"ARQ-OF-20260710 · Arquitectura A202 / p. 13, A301 / p. 16","appearanceStatus":"criterio_visual","appearanceBasis":"Interpretación visual del material documental; el acabado, tono y parámetros PBR no son una especificación contractual.","note":"La apariencia gráfica no modifica ni confirma la especificación física del material."} | {"elementId":"office_0207","ifcGuid":"3eam8b4zrTLeQ2SItk81W0","ifcClass":"IfcSlab","buildingId":"office","buildingName":"Edificio de oficinas","sourceDocumentId":"ARQ-OF-20260710","sourceRepresentationKind":"documentary_mesh"} | {"layerId":"structure","layerName":"Estructura","role":"Losa","basis":"Clasificación por función del elemento; no modifica las especificaciones documentales."} | structure | {"profileId":"concrete_reinforced","name":"Hormigón armado · gris natural","status":"criterio_visual","basis":"Interpretación visual del material documental; el acabado, tono y parámetros PBR no son una especificación contractual.","physicalMaterialUnchanged":true} | Estructura | V0.1 · Reconstrucción documental y coordinación preliminar | Hormigón armado | Estructura | Hormigón armado · gris natural | criterio_visual | ARQ-OF-20260710 · Arquitectura A202 / p. 13, A301 / p. 16 | known | concrete_reinforced | [0.666667,0.662745,0.619608] | 0.96 | Interpretación visual del material documental; el acabado, tono y parámetros PBR no son una especificación contractual. | Estructura; BIM · Estructura | Hormigón armado | 20 × 10 × 0.2 | 285.11 | 285.31 | 40 | ARQ-OF-20260710 · Arquitectura A202 / p. 13, A301 / p. 16 | Edificio de oficinas | Espesor de losa documentado; cota deducida de 200 mm de losa, cámara de 500 mm, aislamiento de 100 mm y acabado de 40 mm. | Coordenadas de proyecto en metros; sumar (729400, 4301550, 285) para recuperar las coordenadas UTM y cotas de los planos. | Reconstrucción tridimensional de la documentación y revisión preliminar de coordinación; pendiente de revisión por el equipo de diseño. | Malla cerrada, orientación coherente de las caras y volumen positivo. | Plano general U004 de 2026-07-31; geometría vectorial del PDF registrada con las coordenadas de lindero indicadas. | Registro de líneas del PDF general, envolvente de 20 × 10 m; eje local 1 al norte y acceso del lado A al oeste. Estimación de trabajo de implantación de ±0,15 m, pendiente de CAD; no constituye una precisión topográfica garantizada. | office_0207 | Sólido de malla triangular cerrada en IFC4 | Volumen exclusivamente geométrico; los espesores de representación, las simplificaciones y las envolventes no constituyen mediciones de compra, ejecución, fabricación ni volumen neto de material. | 285.95 | El plano general de 2026-07-31 mantiene el edificio de oficinas de 200 m², mientras documentación anterior indica su supresión. Se conserva lo dibujado, pendiente de confirmación de la propiedad y del equipo de diseño. | JH_Trazabilidad - Observaciones: Cámara ventilada de 500 mm conservada como vacío; casetones y armaduras no modelados.
Placa alveolar prefabricada de cubierta de oficinas · 200 mm · volumen bruto | Planta baja | Losa | ROOF | Planos de estructura del edificio de oficinas | office_0210 | 12.6309 | 21.1757 | 0.2 | 412 | 40 | office | Edificio de oficinas | Planta baja | {"name":"Hormigón prefabricado pretensado","source":"EST-OF-20260710 · Estructura B103 / p. 4","status":"known"} | {"documented":[],"geometry":[{"label":"Dimensiones de la caja local del elemento (X, Y, Z)","value":"20 × 10 × 0.2","unit":"m","source":"Malla triangulada del elemento en ejes locales del edificio","status":"derivado"},{"label":"Cota mínima absoluta de la malla","value":290.15,"unit":"m","source":"Malla de proyecto y origen altimétrico 285 m","status":"derivado"},{"label":"Cota máxima absoluta de la malla","value":290.35,"unit":"m","source":"Malla de proyecto y origen altimétrico 285 m","status":"derivado"},{"label":"Volumen geométrico bruto","value":40.0,"unit":"m³","source":"Malla cerrada del elemento","status":"derivado"}],"notes":["Las dimensiones documentadas proceden de anotaciones o cuadros; la caja y el volumen se calculan a partir de la malla.","El volumen es exclusivamente geométrico y bruto; no representa una medición neta de material ni una cantidad de compra."]} | {"documentId":"EST-OF-20260710","title":"Planos de estructura del edificio de oficinas","date":"2026-07-10","sheet":"Estructura B103 / p. 4"} | provisional | {"horizontalStatus":"derivado","verticalStatus":"provisional","baseElevationM":285.95,"note":"Registro de líneas del PDF general, envolvente de 20 × 10 m; eje local 1 al norte y acceso del lado A al oeste. Estimación de trabajo de implantación de ±0,15 m, pendiente de CAD; no constituye una precisión topográfica garantizada."} | ["Arquitectura A301 indica placa prefabricada de 250 mm y capa de compresión de 50 mm; el modelo adopta 200 + 50 mm según estructura.","El plano general de 2026-07-31 mantiene el edificio de oficinas de 200 m², mientras documentación anterior indica su supresión. Se conserva lo dibujado, pendiente de confirmación de la propiedad y del equipo de diseño.","Conductos de pretensado y alvéolos no modelados. El volumen del sólido es bruto y no equivale al volumen neto de hormigón.","Registro de líneas del PDF general, envolvente de 20 × 10 m; eje local 1 al norte y acceso del lado A al oeste. Estimación de trabajo de implantación de ±0,15 m, pendiente de CAD; no constituye una precisión topográfica garantizada."] | {"boundingBoxM":{"min":[14.818557,71.742172,5.15],"max":[27.449443,92.917828,5.35]},"extentsM":[12.630886,21.175656,0.2],"meshSurfaceM2":412.0,"meshVolumeM3":40.0,"closedSolid":true,"basis":"Geometría triangulada releída del IFC; envolventes y magnitudes no contractuales."} | {"material":true,"document":true,"quantities":true,"containerGuid":"3ztlotcerHPueDgxP84R6z","containerName":"Planta baja"} | {"id":"structure","name":"Estructura"} | {"profileId":"concrete_prestressed","name":"Placa alveolar prefabricada","materialName":"Hormigón prefabricado pretensado","physicalMaterialStatus":"known","physicalMaterialSource":"EST-OF-20260710 · Estructura B103 / p. 4","appearanceStatus":"criterio_visual","appearanceBasis":"Interpretación visual del material documental; el acabado, tono y parámetros PBR no son una especificación contractual.","note":"La apariencia gráfica no modifica ni confirma la especificación física del material."} | {"elementId":"office_0210","ifcGuid":"3C$qiZki9QcgHf2jgAqrmO","ifcClass":"IfcSlab","buildingId":"office","buildingName":"Edificio de oficinas","sourceDocumentId":"EST-OF-20260710","sourceRepresentationKind":"documentary_mesh"} | {"layerId":"structure","layerName":"Estructura","role":"Losa","basis":"Clasificación por función del elemento; no modifica las especificaciones documentales."} | structure | {"profileId":"concrete_prestressed","name":"Placa alveolar prefabricada","status":"criterio_visual","basis":"Interpretación visual del material documental; el acabado, tono y parámetros PBR no son una especificación contractual.","physicalMaterialUnchanged":true} | Estructura | V0.1 · Reconstrucción documental y coordinación preliminar | Hormigón prefabricado pretensado | Estructura | Placa alveolar prefabricada | criterio_visual | EST-OF-20260710 · Estructura B103 / p. 4 | known | concrete_prestressed | [0.729412,0.733333,0.698039] | 0.88 | Interpretación visual del material documental; el acabado, tono y parámetros PBR no son una especificación contractual. | Estructura; BIM · Estructura | Hormigón prefabricado pretensado | 20 × 10 × 0.2 | 290.15 | 290.35 | 40 | EST-OF-20260710 · Estructura B103 / p. 4 | Edificio de oficinas | Espesor de placa prefabricada de 200 mm documentado; los alvéolos se representan mediante una envolvente maciza bruta. | Coordenadas de proyecto en metros; sumar (729400, 4301550, 285) para recuperar las coordenadas UTM y cotas de los planos. | Reconstrucción tridimensional de la documentación y revisión preliminar de coordinación; pendiente de revisión por el equipo de diseño. | Malla cerrada, orientación coherente de las caras y volumen positivo. | Plano general U004 de 2026-07-31; geometría vectorial del PDF registrada con las coordenadas de lindero indicadas. | Registro de líneas del PDF general, envolvente de 20 × 10 m; eje local 1 al norte y acceso del lado A al oeste. Estimación de trabajo de implantación de ±0,15 m, pendiente de CAD; no constituye una precisión topográfica garantizada. | office_0210 | Sólido de malla triangular cerrada en IFC4 | Volumen exclusivamente geométrico; los espesores de representación, las simplificaciones y las envolventes no constituyen mediciones de compra, ejecución, fabricación ni volumen neto de material. | 285.95 | El plano general de 2026-07-31 mantiene el edificio de oficinas de 200 m², mientras documentación anterior indica su supresión. Se conserva lo dibujado, pendiente de confirmación de la propiedad y del equipo de diseño. | JH_Trazabilidad - Discrepancia pendiente: Arquitectura A301 indica placa prefabricada de 250 mm y capa de compresión de 50 mm; el modelo adopta 200 + 50 mm según estructura.; Simplificación de los alvéolos: Conductos de pretensado y alvéolos no modelados. El volumen del sólido es bruto y no equivale al volumen neto de hormigón.
Capa de compresión de cubierta de oficinas · 50 mm | Planta baja | Losa | ROOF | Planos de estructura del edificio de oficinas | office_0211 | 12.6309 | 21.1757 | 0.05 | 403 | 10 | office | Edificio de oficinas | Planta baja | {"name":"Hormigón de áridos finos HA-25","source":"EST-OF-20260710 · Estructura B103 / p. 4","status":"known"} | {"documented":[{"label":"Espesor","value":0.05,"unit":"m","source":"EST-OF-20260710 · Estructura B103 / p. 4","status":"documentado"}],"geometry":[{"label":"Dimensiones de la caja local del elemento (X, Y, Z)","value":"20 × 10 × 0.05","unit":"m","source":"Malla triangulada del elemento en ejes locales del edificio","status":"derivado"},{"label":"Cota mínima absoluta de la malla","value":290.35,"unit":"m","source":"Malla de proyecto y origen altimétrico 285 m","status":"derivado"},{"label":"Cota máxima absoluta de la malla","value":290.4,"unit":"m","source":"Malla de proyecto y origen altimétrico 285 m","status":"derivado"},{"label":"Volumen geométrico bruto","value":10.0,"unit":"m³","source":"Malla cerrada del elemento","status":"derivado"}],"notes":["Las dimensiones documentadas proceden de anotaciones o cuadros; la caja y el volumen se calculan a partir de la malla.","El volumen es exclusivamente geométrico y bruto; no representa una medición neta de material ni una cantidad de compra."]} | {"documentId":"EST-OF-20260710","title":"Planos de estructura del edificio de oficinas","date":"2026-07-10","sheet":"Estructura B103 / p. 4"} | provisional | {"horizontalStatus":"derivado","verticalStatus":"provisional","baseElevationM":285.95,"note":"Registro de líneas del PDF general, envolvente de 20 × 10 m; eje local 1 al norte y acceso del lado A al oeste. Estimación de trabajo de implantación de ±0,15 m, pendiente de CAD; no constituye una precisión topográfica garantizada."} | ["El plano general de 2026-07-31 mantiene el edificio de oficinas de 200 m², mientras documentación anterior indica su supresión. Se conserva lo dibujado, pendiente de confirmación de la propiedad y del equipo de diseño.","Registro de líneas del PDF general, envolvente de 20 × 10 m; eje local 1 al norte y acceso del lado A al oeste. Estimación de trabajo de implantación de ±0,15 m, pendiente de CAD; no constituye una precisión topográfica garantizada."] | {"boundingBoxM":{"min":[14.818557,71.742172,5.35],"max":[27.449443,92.917828,5.4]},"extentsM":[12.630886,21.175656,0.05],"meshSurfaceM2":403.0,"meshVolumeM3":10.0,"closedSolid":true,"basis":"Geometría triangulada releída del IFC; envolventes y magnitudes no contractuales."} | {"material":true,"document":true,"quantities":true,"containerGuid":"3ztlotcerHPueDgxP84R6z","containerName":"Planta baja"} | {"id":"structure","name":"Estructura"} | {"profileId":"concrete_ha25","name":"Capa de compresión HA-25","materialName":"Hormigón de áridos finos HA-25","physicalMaterialStatus":"known","physicalMaterialSource":"EST-OF-20260710 · Estructura B103 / p. 4","appearanceStatus":"criterio_visual","appearanceBasis":"Interpretación visual del material documental; el acabado, tono y parámetros PBR no son una especificación contractual.","note":"La apariencia gráfica no modifica ni confirma la especificación física del material."} | {"elementId":"office_0211","ifcGuid":"1Gc5D2Vz9PQeoxWaKo2KyF","ifcClass":"IfcSlab","buildingId":"office","buildingName":"Edificio de oficinas","sourceDocumentId":"EST-OF-20260710","sourceRepresentationKind":"documentary_mesh"} | {"layerId":"structure","layerName":"Estructura","role":"Losa","basis":"Clasificación por función del elemento; no modifica las especificaciones documentales."} | structure | {"profileId":"concrete_ha25","name":"Capa de compresión HA-25","status":"criterio_visual","basis":"Interpretación visual del material documental; el acabado, tono y parámetros PBR no son una especificación contractual.","physicalMaterialUnchanged":true} | Estructura | V0.1 · Reconstrucción documental y coordinación preliminar | Hormigón de áridos finos HA-25 | Estructura | Capa de compresión HA-25 | criterio_visual | EST-OF-20260710 · Estructura B103 / p. 4 | known | concrete_ha25 | [0.709804,0.705882,0.658824] | 0.96 | Interpretación visual del material documental; el acabado, tono y parámetros PBR no son una especificación contractual. | Estructura; BIM · Estructura | Hormigón de áridos finos HA-25 | 20 × 10 × 0.05 | 290.35 | 290.4 | 10 | EST-OF-20260710 · Estructura B103 / p. 4 | Edificio de oficinas | Cara superior estructural a +4,450 m documentada; diferencia de 50 mm respecto a la cota +4,400 m de arquitectura. | Coordenadas de proyecto en metros; sumar (729400, 4301550, 285) para recuperar las coordenadas UTM y cotas de los planos. | Reconstrucción tridimensional de la documentación y revisión preliminar de coordinación; pendiente de revisión por el equipo de diseño. | Malla cerrada, orientación coherente de las caras y volumen positivo. | Plano general U004 de 2026-07-31; geometría vectorial del PDF registrada con las coordenadas de lindero indicadas. | Registro de líneas del PDF general, envolvente de 20 × 10 m; eje local 1 al norte y acceso del lado A al oeste. Estimación de trabajo de implantación de ±0,15 m, pendiente de CAD; no constituye una precisión topográfica garantizada. | office_0211 | Sólido de malla triangular cerrada en IFC4 | Volumen exclusivamente geométrico; los espesores de representación, las simplificaciones y las envolventes no constituyen mediciones de compra, ejecución, fabricación ni volumen neto de material. | 285.95 | El plano general de 2026-07-31 mantiene el edificio de oficinas de 200 m², mientras documentación anterior indica su supresión. Se conserva lo dibujado, pendiente de confirmación de la propiedad y del equipo de diseño. | JH_Trazabilidad - Espesor (m): 0.05; JH_DimensionesDocumentadas - Espesor: 0.05 m

# IfcSlab: Cimentación industrial (108)
In: Parcela industrial Jinhong
Description: Cimentación industrial; PredefinedType: USERDEFINED; Document: Cimentaciones de equipos y pedestales del fabricante · revisión recibida 04/09/2026; Group: Zona de separación de aire; BIM · Cimentaciones
JH_InformacionBIM - status: provisional; buildingId: process_plant; buildingName: Zona de separación de aire; category: Cimentación industrial; representationKind: foundation; geometryStatus: Geometría de fabricante; implantación absoluta provisional; ifcClass: IfcSlab; visualLayer: {"id":"foundations","name":"Cimentaciones"}; componentSeparation: {"status":"objeto_independiente","note":"Control de visibilidad del objeto completo; la clasificación no altera la malla."}; classification: {"layerId":"foundations","layerName":"Cimentaciones","role":"Cimentación industrial","basis":"Clasificación por función del elemento; no modifica las especificaciones documentales."}; layerId: foundations
JH_Trazabilidad - Documento de origen: Cimentaciones de equipos y pedestales del fabricante · revisión recibida 04/09/2026; Referencia vertical: Cotas relativas del dibujo. La equivalencia con un datum absoluto está pendiente.; Implantación para visualización: Z del modelo = cota relativa + 1,10 m. Correspondencia provisional con 286,10 m; no es cota de obra confirmada.; Capa BIM: Cimentaciones; Estado del acabado: criterio_visual; Categoria: Cimentación industrial; ClaseIFC: IfcSlab; EstadoDeInformacion: provisional; UsoDeLasMagnitudes: Geometría de coordinación. Los volúmenes de referencia y subcomponentes no son cantidades de material ni componentes de fabricación certificados.
JH_CapaBIM - IdentificadorCapa: foundations; NombreCapa: Cimentaciones; Funcion: Cimentación industrial; VisibilidadInicial: yes
JH_AcabadoVisual - Metallicidad: 0; Estado: criterio_visual; Referencia: Interpretación visual del material documental; el acabado, tono y parámetros PBR no son una especificación contractual.; Nota: La apariencia no certifica el material físico ni el acabado de fabricación.
Name | Material | Extensión de la malla en X (m) = ExtensionX (m) | Extensión de la malla en Y (m) = ExtensionY (m) | Extensión de la malla en Z (m) = ExtensionZ (m) = Espesor o altura real de sección (m) | Cota inferior de visualización (m) | Cota superior de visualización (m) | SuperficieDeLaMalla (m2) | VolumenGeometrico (m3) | JH_InformacionBIM, source = DocumentoFuente | material | dimensions | issues = IncidenciasPendientes | positioning = PosicionYEstado | assemblyId = Conjunto de cimentación | equipmentIds | supportPositionIds | sectionRef = Sección de referencia | sourceCadHandles | stableElementKey | geometryMetrics | materialAppearance | visualizationIdentity | appearance | Equipos asociados | Identificadores CAD de referencia | JH_Trazabilidad, Material = name | Cota inferior relativa (m) = Cota inferior relativa adoptada (m) | Cota superior relativa (m) = Cota superior relativa adoptada (m) | Área de planta (m²) | Volumen geométrico (m³) | Estado de la geometría | Acabado de visualización = Acabado | Identificador | status | JH_EvidenciaDeMaterial, source | Extensión local X (m) | Extensión local Y (m) | Perfil | ColorRGB | Rugosidad | Incidencias de origen
Cimentación común MAC · capa de limpieza | Hormigón de limpieza HA-20 | 19.198 | 11.6786 | 0.1 | 285 | 285.1 | 342.14 | 16.833 | {"documentId":"LHD2609-JG00100-20260904","title":"Cimentaciones de equipos y pedestales del fabricante · revisión recibida 04/09/2026","date":"2026-09-04","sheet":"1–1","fileName":"LHD2609-JG00100_20260904.dwg","revisionCaveat":"Fecha de revisión tomada del nombre recibido; cajetines internos mantienen 02/07/2026 y algunos textos de plantilla.","sourceFileSha256":"b42eb027b7bc0b14c38d1d13514f4899b58a732aa8d0ba2ccf10fa2fc3192890"} | {"name":"Hormigón de limpieza HA-20","status":"documentado","source":"Secciones del fabricante: capa de limpieza de 100 mm; nota 2CED5"} | {"documented":[{"label":"Extensión local X","value":18.1,"unit":"m","source":"23B3/23B8, 23B3/23CC, 23B3/23CD, 23B3/23D0, 288F5","status":"derivada del contorno CAD"},{"label":"Extensión local Y","value":9.3,"unit":"m","source":"23B3/23B8, 23B3/23CC, 23B3/23CD, 23B3/23D0, 288F5","status":"derivada del contorno CAD"},{"label":"Cota inferior relativa adoptada","value":-1.1,"unit":"m","source":"1–1","status":"documentada"},{"label":"Cota superior relativa adoptada","value":-1,"unit":"m","source":"1–1","status":"documentada / separación por material"}],"geometry":[{"label":"Extensión de la malla en X","value":19.198019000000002,"unit":"m","source":"Geometría releída del IFC; datum absoluto de proceso provisional","status":"derivado"},{"label":"Extensión de la malla en Y","value":11.678623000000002,"unit":"m","source":"Geometría releída del IFC; datum absoluto de proceso provisional","status":"derivado"},{"label":"Extensión de la malla en Z","value":0.1,"unit":"m","source":"Geometría releída del IFC; datum absoluto de proceso provisional","status":"derivado"},{"label":"Cota inferior de visualización","value":285.0,"unit":"m","source":"Geometría releída del IFC; datum absoluto de proceso provisional","status":"derivado"},{"label":"Cota superior de visualización","value":285.1,"unit":"m","source":"Geometría releída del IFC; datum absoluto de proceso provisional","status":"derivado"}]} | [] | {"Cota inferior relativa (m)":-1.1,"Cota superior relativa (m)":-1,"Cero absoluto de visualización (m)":286.1,"Estado del cero absoluto":"Provisional","Criterio":"Las cotas relativas proceden del dibujo; la equivalencia absoluta no está confirmada."} | F-MAC | ["AC1001A","AC1001B","AC1001C"] | [] | 1–1 | ["23B3/23B8","23B3/23CC","23B3/23CD","23B3/23D0","288F5","23B3/23C7","23B3/F6F1","288F5","23B3/23C5","23B3/F6F1","288F5","23B3/23C4","23B3/F6F1","288F5"] | F-MAC/Cimentación común MAC · capa de limpieza | {"boundingBoxM":{"min":[46.451656,66.617308,0.0],"max":[65.649675,78.295931,0.1]},"extentsM":[19.198019,11.678623,0.1],"meshSurfaceM2":342.139996,"meshVolumeM3":16.833,"closedSolid":true,"basis":"Magnitudes de las mallas representadas, no cantidades certificadas de obra, compra o fabricación. Las partes pueden compartir superficies; no se suman como un despiece de materiales."} | {"profileId":"concrete_ha20","name":"Hormigón de limpieza HA-20","materialName":"Hormigón de limpieza HA-20","physicalMaterialStatus":"documentado","physicalMaterialSource":"Secciones del fabricante: capa de limpieza de 100 mm; nota 2CED5","appearanceStatus":"criterio_visual","appearanceBasis":"Interpretación visual del material documental; el acabado, tono y parámetros PBR no son una especificación contractual.","note":"La apariencia gráfica no modifica ni confirma la especificación física del material."} | {"elementId":"found_0904_b1416cc77686d5","ifcGuid":"2V_cyDgWPItuB7IZnAbcVY","ifcClass":"IfcSlab","buildingId":"process_plant","buildingName":"Zona de separación de aire","sourceDocumentId":"LHD2609-JG00100-20260904","sourceRepresentationKind":"foundation"} | {"profileId":"concrete_ha20","name":"Hormigón de limpieza HA-20","status":"criterio_visual","basis":"Interpretación visual del material documental; el acabado, tono y parámetros PBR no son una especificación contractual.","physicalMaterialUnchanged":true} | AC1001A, AC1001B, AC1001C | 23B3/23B8, 23B3/23CC, 23B3/23CD, 23B3/23D0, 288F5 | Hormigón de limpieza HA-20 | -1.1 | -1 | 168.33 | 16.833 | Contornos y sección documentados por el fabricante | Hormigón de limpieza HA-20 | found_0904_b1416cc77686d5 | documentado | Secciones del fabricante: capa de limpieza de 100 mm; nota 2CED5 | 18.1 | 9.3 | concrete_ha20 | [0.721569,0.709804,0.658824] | 0.98
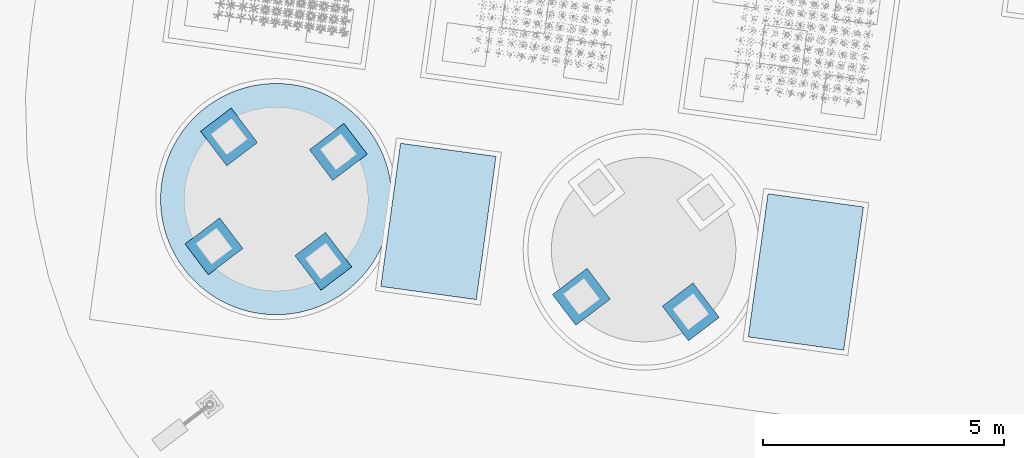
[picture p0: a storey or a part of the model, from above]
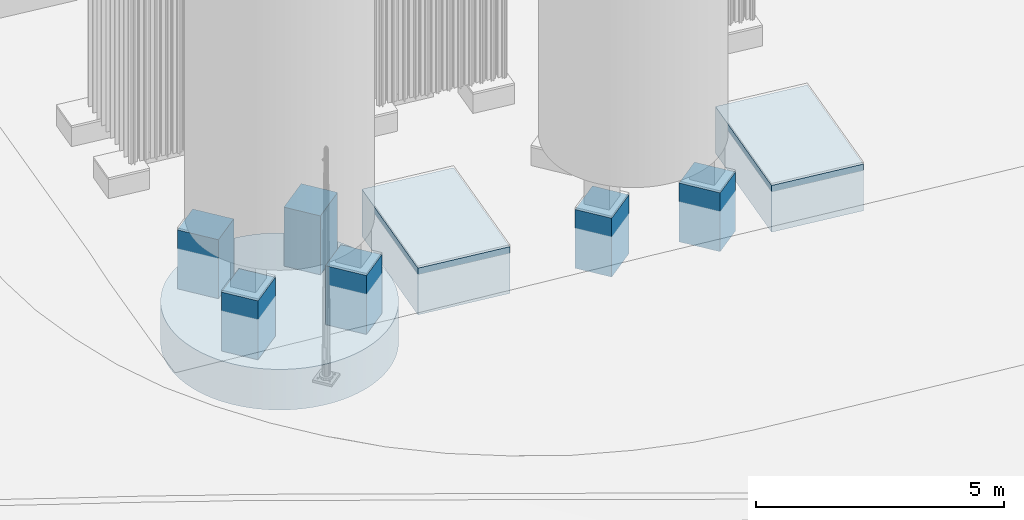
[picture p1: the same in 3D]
Properties of the parts of a building model (IFC4), part 102 of 134

# IfcSlab: Cimentación industrial (108)
Name | Material | Extensión de la malla en X (m) = ExtensionX (m) | Extensión de la malla en Y (m) = ExtensionY (m) | Extensión de la malla en Z (m) = ExtensionZ (m) = Espesor o altura real de sección (m) | Cota inferior de visualización (m) | Cota superior de visualización (m) | SuperficieDeLaMalla (m2) | VolumenGeometrico (m3) | JH_InformacionBIM, source = DocumentoFuente | material | dimensions | issues = IncidenciasPendientes | positioning = PosicionYEstado | assemblyId = Conjunto de cimentación | equipmentIds | supportPositionIds | sectionRef = Sección de referencia | sourceCadHandles | stableElementKey | geometryMetrics | materialAppearance | visualizationIdentity | appearance | Equipos asociados | Identificadores CAD de referencia | JH_Trazabilidad, Material = name | Cota inferior relativa (m) = Cota inferior relativa adoptada (m) | Cota superior relativa (m) = Cota superior relativa adoptada (m) | Área de planta (m²) | Volumen geométrico (m³) | Estado de la geometría | Acabado de visualización = Acabado | Identificador | status | JH_EvidenciaDeMaterial, source | Extensión local X (m) | Extensión local Y (m) | Perfil | ColorRGB | Rugosidad | Incidencias de origen
Plinto del compresor AC1001A · mortero de asiento | Mortero HA-35 de alta resistencia sin retracción | 3.43758 | 5.91556 | 0.05 | 286.45 | 286.5 | 31.07 | 0.756 | {"documentId":"LHD2609-JG00100-20260904","title":"Cimentaciones de equipos y pedestales del fabricante · revisión recibida 04/09/2026","date":"2026-09-04","sheet":"1–1","fileName":"LHD2609-JG00100_20260904.dwg","revisionCaveat":"Fecha de revisión tomada del nombre recibido; cajetines internos mantienen 02/07/2026 y algunos textos de plantilla.","sourceFileSha256":"b42eb027b7bc0b14c38d1d13514f4899b58a732aa8d0ba2ccf10fa2fc3192890"} | {"name":"Mortero HA-35 de alta resistencia sin retracción","status":"documentado","source":"Capa superior de 50 mm expresada en las secciones del fabricante"} | {"documented":[{"label":"Extensión local X","value":2.7,"unit":"m","source":"23B3/23C7, 23B3/F6F1, 288F5","status":"derivada del contorno CAD"},{"label":"Extensión local Y","value":5.6,"unit":"m","source":"23B3/23C7, 23B3/F6F1, 288F5","status":"derivada del contorno CAD"},{"label":"Cota inferior relativa adoptada","value":0.35,"unit":"m","source":"1–1","status":"documentada"},{"label":"Cota superior relativa adoptada","value":0.4,"unit":"m","source":"1–1","status":"documentada / separación por material"}],"geometry":[{"label":"Extensión de la malla en X","value":3.437579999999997,"unit":"m","source":"Geometría releída del IFC; datum absoluto de proceso provisional","status":"derivado"},{"label":"Extensión de la malla en Y","value":5.915563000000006,"unit":"m","source":"Geometría releída del IFC; datum absoluto de proceso provisional","status":"derivado"},{"label":"Extensión de la malla en Z","value":0.050000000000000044,"unit":"m","source":"Geometría releída del IFC; datum absoluto de proceso provisional","status":"derivado"},{"label":"Cota inferior de visualización","value":286.45,"unit":"m","source":"Geometría releída del IFC; datum absoluto de proceso provisional","status":"derivado"},{"label":"Cota superior de visualización","value":286.5,"unit":"m","source":"Geometría releída del IFC; datum absoluto de proceso provisional","status":"derivado"}]} | [] | {"Cota inferior relativa (m)":0.35,"Cota superior relativa (m)":0.4,"Cero absoluto de visualización (m)":286.1,"Estado del cero absoluto":"Provisional","Criterio":"Las cotas relativas proceden del dibujo; la equivalencia absoluta no está confirmada."} | F-MAC | ["AC1001A"] | [] | 1–1 | ["23B3/23C7","23B3/F6F1","288F5"] | F-MAC/Plinto del compresor AC1001A · mortero de asiento | {"boundingBoxM":{"min":[48.05281,70.81635,1.45],"max":[51.49039,76.731913,1.5]},"extentsM":[3.43758,5.915563,0.05],"meshSurfaceM2":31.069997,"meshVolumeM3":0.756,"closedSolid":true,"basis":"Magnitudes de las mallas representadas, no cantidades certificadas de obra, compra o fabricación. Las partes pueden compartir superficies; no se suman como un despiece de materiales."} | {"profileId":"grout_ha35","name":"Grout HA-35 sin retracción","materialName":"Mortero HA-35 de alta resistencia sin retracción","physicalMaterialStatus":"documentado","physicalMaterialSource":"Capa superior de 50 mm expresada en las secciones del fabricante","appearanceStatus":"criterio_visual","appearanceBasis":"Interpretación visual del material documental; el acabado, tono y parámetros PBR no son una especificación contractual.","note":"La apariencia gráfica no modifica ni confirma la especificación física del material."} | {"elementId":"found_0904_2eb7063ff00889","ifcGuid":"0e916udunPw9MUPtpVWrSE","ifcClass":"IfcSlab","buildingId":"process_plant","buildingName":"Zona de separación de aire","sourceDocumentId":"LHD2609-JG00100-20260904","sourceRepresentationKind":"foundation"} | {"profileId":"grout_ha35","name":"Grout HA-35 sin retracción","status":"criterio_visual","basis":"Interpretación visual del material documental; el acabado, tono y parámetros PBR no son una especificación contractual.","physicalMaterialUnchanged":true} | AC1001A | 23B3/23C7, 23B3/F6F1, 288F5 | Mortero HA-35 de alta resistencia sin retracción | 0.35 | 0.4 | 15.12 | 0.756 | Contornos y sección documentados por el fabricante | Grout HA-35 sin retracción | found_0904_2eb7063ff00889 | documentado | Capa superior de 50 mm expresada en las secciones del fabricante | 2.7 | 5.6 | grout_ha35 | [0.792157,0.776471,0.721569] | 0.94
Plinto del compresor AC1001B · mortero de asiento | Mortero HA-35 de alta resistencia sin retracción | 3.43758 | 5.91556 | 0.05 | 286.45 | 286.5 | 31.07 | 0.756 | {"documentId":"LHD2609-JG00100-20260904","title":"Cimentaciones de equipos y pedestales del fabricante · revisión recibida 04/09/2026","date":"2026-09-04","sheet":"1–1","fileName":"LHD2609-JG00100_20260904.dwg","revisionCaveat":"Fecha de revisión tomada del nombre recibido; cajetines internos mantienen 02/07/2026 y algunos textos de plantilla.","sourceFileSha256":"b42eb027b7bc0b14c38d1d13514f4899b58a732aa8d0ba2ccf10fa2fc3192890"} | {"name":"Mortero HA-35 de alta resistencia sin retracción","status":"documentado","source":"Capa superior de 50 mm expresada en las secciones del fabricante"} | {"documented":[{"label":"Extensión local X","value":2.7,"unit":"m","source":"23B3/23C5, 23B3/F6F1, 288F5","status":"derivada del contorno CAD"},{"label":"Extensión local Y","value":5.6,"unit":"m","source":"23B3/23C5, 23B3/F6F1, 288F5","status":"derivada del contorno CAD"},{"label":"Cota inferior relativa adoptada","value":0.35,"unit":"m","source":"1–1","status":"documentada"},{"label":"Cota superior relativa adoptada","value":0.4,"unit":"m","source":"1–1","status":"documentada / separación por material"}],"geometry":[{"label":"Extensión de la malla en X","value":3.437580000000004,"unit":"m","source":"Geometría releída del IFC; datum absoluto de proceso provisional","status":"derivado"},{"label":"Extensión de la malla en Y","value":5.915563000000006,"unit":"m","source":"Geometría releída del IFC; datum absoluto de proceso provisional","status":"derivado"},{"label":"Extensión de la malla en Z","value":0.050000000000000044,"unit":"m","source":"Geometría releída del IFC; datum absoluto de proceso provisional","status":"derivado"},{"label":"Cota inferior de visualización","value":286.45,"unit":"m","source":"Geometría releída del IFC; datum absoluto de proceso provisional","status":"derivado"},{"label":"Cota superior de visualización","value":286.5,"unit":"m","source":"Geometría releída del IFC; datum absoluto de proceso provisional","status":"derivado"}]} | [] | {"Cota inferior relativa (m)":0.35,"Cota superior relativa (m)":0.4,"Cero absoluto de visualización (m)":286.1,"Estado del cero absoluto":"Provisional","Criterio":"Las cotas relativas proceden del dibujo; la equivalencia absoluta no está confirmada."} | F-MAC | ["AC1001B"] | [] | 1–1 | ["23B3/23C5","23B3/F6F1","288F5"] | F-MAC/Plinto del compresor AC1001B · mortero de asiento | {"boundingBoxM":{"min":[54.393167,69.944645,1.45],"max":[57.830747,75.860208,1.5]},"extentsM":[3.43758,5.915563,0.05],"meshSurfaceM2":31.069997,"meshVolumeM3":0.756,"closedSolid":true,"basis":"Magnitudes de las mallas representadas, no cantidades certificadas de obra, compra o fabricación. Las partes pueden compartir superficies; no se suman como un despiece de materiales."} | {"profileId":"grout_ha35","name":"Grout HA-35 sin retracción","materialName":"Mortero HA-35 de alta resistencia sin retracción","physicalMaterialStatus":"documentado","physicalMaterialSource":"Capa superior de 50 mm expresada en las secciones del fabricante","appearanceStatus":"criterio_visual","appearanceBasis":"Interpretación visual del material documental; el acabado, tono y parámetros PBR no son una especificación contractual.","note":"La apariencia gráfica no modifica ni confirma la especificación física del material."} | {"elementId":"found_0904_462144d3303736","ifcGuid":"1tPpMkTW9HHxqHd9jZyMB_","ifcClass":"IfcSlab","buildingId":"process_plant","buildingName":"Zona de separación de aire","sourceDocumentId":"LHD2609-JG00100-20260904","sourceRepresentationKind":"foundation"} | {"profileId":"grout_ha35","name":"Grout HA-35 sin retracción","status":"criterio_visual","basis":"Interpretación visual del material documental; el acabado, tono y parámetros PBR no son una especificación contractual.","physicalMaterialUnchanged":true} | AC1001B | 23B3/23C5, 23B3/F6F1, 288F5 | Mortero HA-35 de alta resistencia sin retracción | 0.35 | 0.4 | 15.12 | 0.756 | Contornos y sección documentados por el fabricante | Grout HA-35 sin retracción | found_0904_462144d3303736 | documentado | Capa superior de 50 mm expresada en las secciones del fabricante | 2.7 | 5.6 | grout_ha35 | [0.792157,0.776471,0.721569] | 0.94
Plinto del compresor AC1001C · mortero de asiento | Mortero HA-35 de alta resistencia sin retracción | 3.43758 | 5.91556 | 0.05 | 286.45 | 286.5 | 31.07 | 0.756 | {"documentId":"LHD2609-JG00100-20260904","title":"Cimentaciones de equipos y pedestales del fabricante · revisión recibida 04/09/2026","date":"2026-09-04","sheet":"1–1","fileName":"LHD2609-JG00100_20260904.dwg","revisionCaveat":"Fecha de revisión tomada del nombre recibido; cajetines internos mantienen 02/07/2026 y algunos textos de plantilla.","sourceFileSha256":"b42eb027b7bc0b14c38d1d13514f4899b58a732aa8d0ba2ccf10fa2fc3192890"} | {"name":"Mortero HA-35 de alta resistencia sin retracción","status":"documentado","source":"Capa superior de 50 mm expresada en las secciones del fabricante"} | {"documented":[{"label":"Extensión local X","value":2.7,"unit":"m","source":"23B3/23C4, 23B3/F6F1, 288F5","status":"derivada del contorno CAD"},{"label":"Extensión local Y","value":5.6,"unit":"m","source":"23B3/23C4, 23B3/F6F1, 288F5","status":"derivada del contorno CAD"},{"label":"Cota inferior relativa adoptada","value":0.35,"unit":"m","source":"1–1","status":"documentada"},{"label":"Cota superior relativa adoptada","value":0.4,"unit":"m","source":"1–1","status":"documentada / separación por material"}],"geometry":[{"label":"Extensión de la malla en X","value":3.4375809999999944,"unit":"m","source":"Geometría releída del IFC; datum absoluto de proceso provisional","status":"derivado"},{"label":"Extensión de la malla en Y","value":5.915563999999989,"unit":"m","source":"Geometría releída del IFC; datum absoluto de proceso provisional","status":"derivado"},{"label":"Extensión de la malla en Z","value":0.050000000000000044,"unit":"m","source":"Geometría releída del IFC; datum absoluto de proceso provisional","status":"derivado"},{"label":"Cota inferior de visualización","value":286.45,"unit":"m","source":"Geometría releída del IFC; datum absoluto de proceso provisional","status":"derivado"},{"label":"Cota superior de visualización","value":286.5,"unit":"m","source":"Geometría releída del IFC; datum absoluto de proceso provisional","status":"derivado"}]} | [] | {"Cota inferior relativa (m)":0.35,"Cota superior relativa (m)":0.4,"Cero absoluto de visualización (m)":286.1,"Estado del cero absoluto":"Provisional","Criterio":"Las cotas relativas proceden del dibujo; la equivalencia absoluta no está confirmada."} | F-MAC | ["AC1001C"] | [] | 1–1 | ["23B3/23C4","23B3/F6F1","288F5"] | F-MAC/Plinto del compresor AC1001C · mortero de asiento | {"boundingBoxM":{"min":[60.733524,69.072939,1.45],"max":[64.171105,74.988503,1.5]},"extentsM":[3.437581,5.915564,0.05],"meshSurfaceM2":31.070012,"meshVolumeM3":0.756,"closedSolid":true,"basis":"Magnitudes de las mallas representadas, no cantidades certificadas de obra, compra o fabricación. Las partes pueden compartir superficies; no se suman como un despiece de materiales."} | {"profileId":"grout_ha35","name":"Grout HA-35 sin retracción","materialName":"Mortero HA-35 de alta resistencia sin retracción","physicalMaterialStatus":"documentado","physicalMaterialSource":"Capa superior de 50 mm expresada en las secciones del fabricante","appearanceStatus":"criterio_visual","appearanceBasis":"Interpretación visual del material documental; el acabado, tono y parámetros PBR no son una especificación contractual.","note":"La apariencia gráfica no modifica ni confirma la especificación física del material."} | {"elementId":"found_0904_d317582103e9e0","ifcGuid":"2P5pKdcejJP8q6yMwJ_zdH","ifcClass":"IfcSlab","buildingId":"process_plant","buildingName":"Zona de separación de aire","sourceDocumentId":"LHD2609-JG00100-20260904","sourceRepresentationKind":"foundation"} | {"profileId":"grout_ha35","name":"Grout HA-35 sin retracción","status":"criterio_visual","basis":"Interpretación visual del material documental; el acabado, tono y parámetros PBR no son una especificación contractual.","physicalMaterialUnchanged":true} | AC1001C | 23B3/23C4, 23B3/F6F1, 288F5 | Mortero HA-35 de alta resistencia sin retracción | 0.35 | 0.4 | 15.12 | 0.756 | Contornos y sección documentados por el fabricante | Grout HA-35 sin retracción | found_0904_d317582103e9e0 | documentado | Capa superior de 50 mm expresada en las secciones del fabricante | 2.7 | 5.6 | grout_ha35 | [0.792157,0.776471,0.721569] | 0.94
Base del preenfriador RU1101A · capa de limpieza | Hormigón de limpieza HA-20 | 4.48775 | 2.94969 | 0.1 | 285 | 285.1 | 21.48 | 1.008 | {"documentId":"LHD2609-JG00100-20260904","title":"Cimentaciones de equipos y pedestales del fabricante · revisión recibida 04/09/2026","date":"2026-09-04","sheet":"2–2","fileName":"LHD2609-JG00100_20260904.dwg","revisionCaveat":"Fecha de revisión tomada del nombre recibido; cajetines internos mantienen 02/07/2026 y algunos textos de plantilla.","sourceFileSha256":"b42eb027b7bc0b14c38d1d13514f4899b58a732aa8d0ba2ccf10fa2fc3192890"} | {"name":"Hormigón de limpieza HA-20","status":"documentado","source":"Secciones del fabricante: capa de limpieza de 100 mm; nota 2CED5"} | {"documented":[{"label":"Extensión local X","value":4.2,"unit":"m","source":"2934/2402, 28CEA","status":"derivada del contorno CAD"},{"label":"Extensión local Y","value":2.4,"unit":"m","source":"2934/2402, 28CEA","status":"derivada del contorno CAD"},{"label":"Cota inferior relativa adoptada","value":-1.1,"unit":"m","source":"2–2","status":"interpretación con conflicto conservado"},{"label":"Cota superior relativa adoptada","value":-1,"unit":"m","source":"2–2","status":"documentada / separación por material"}],"geometry":[{"label":"Extensión de la malla en X","value":4.487749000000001,"unit":"m","source":"Geometría releída del IFC; datum absoluto de proceso provisional","status":"derivado"},{"label":"Extensión de la malla en Y","value":2.949689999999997,"unit":"m","source":"Geometría releída del IFC; datum absoluto de proceso provisional","status":"derivado"},{"label":"Extensión de la malla en Z","value":0.1,"unit":"m","source":"Geometría releída del IFC; datum absoluto de proceso provisional","status":"derivado"},{"label":"Cota inferior de visualización","value":285.0,"unit":"m","source":"Geometría releída del IFC; datum absoluto de proceso provisional","status":"derivado"},{"label":"Cota superior de visualización","value":285.1,"unit":"m","source":"Geometría releída del IFC; datum absoluto de proceso provisional","status":"derivado"}]} | ["La etiqueta inferior indica −3,000 m, pero la sección y su cadena 200 + 1000 = 1200 mm indican −1,000 m. Se adopta −1,000 m para la geometría; pendiente de aclaración del fabricante."] | {"Cota inferior relativa (m)":-1.1,"Cota superior relativa (m)":-1,"Cero absoluto de visualización (m)":286.1,"Estado del cero absoluto":"Provisional","Criterio":"Las cotas relativas proceden del dibujo; la equivalencia absoluta no está confirmada."} | F-RU1101A | ["RU1101A"] | [] | 2–2 | ["2934/2402","28CEA"] | F-RU1101A/Base del preenfriador RU1101A · capa de limpieza | {"boundingBoxM":{"min":[46.901246,63.704519,0.0],"max":[51.388995,66.654209,0.1]},"extentsM":[4.487749,2.94969,0.1],"meshSurfaceM2":21.48,"meshVolumeM3":1.008,"closedSolid":true,"basis":"Magnitudes de las mallas representadas, no cantidades certificadas de obra, compra o fabricación. Las partes pueden compartir superficies; no se suman como un despiece de materiales."} | {"profileId":"concrete_ha20","name":"Hormigón de limpieza HA-20","materialName":"Hormigón de limpieza HA-20","physicalMaterialStatus":"documentado","physicalMaterialSource":"Secciones del fabricante: capa de limpieza de 100 mm; nota 2CED5","appearanceStatus":"criterio_visual","appearanceBasis":"Interpretación visual del material documental; el acabado, tono y parámetros PBR no son una especificación contractual.","note":"La apariencia gráfica no modifica ni confirma la especificación física del material."} | {"elementId":"found_0904_5678683977aad3","ifcGuid":"3zANiAvCTT7OvppPO2Stzv","ifcClass":"IfcSlab","buildingId":"process_plant","buildingName":"Zona de separación de aire","sourceDocumentId":"LHD2609-JG00100-20260904","sourceRepresentationKind":"foundation"} | {"profileId":"concrete_ha20","name":"Hormigón de limpieza HA-20","status":"criterio_visual","basis":"Interpretación visual del material documental; el acabado, tono y parámetros PBR no son una especificación contractual.","physicalMaterialUnchanged":true} | RU1101A | 2934/2402, 28CEA | Hormigón de limpieza HA-20 | -1.1 | -1 | 10.08 | 1.008 | Sección y contornos del fabricante; incidencias conservadas | Hormigón de limpieza HA-20 | found_0904_5678683977aad3 | documentado | Secciones del fabricante: capa de limpieza de 100 mm; nota 2CED5 | 4.2 | 2.4 | concrete_ha20 | [0.721569,0.709804,0.658824] | 0.98 | La etiqueta inferior indica −3,000 m, pero la sección y su cadena 200 + 1000 = 1200 mm indican −1,000 m. Se adopta −1,000 m para la geometría; pendiente de aclaración del fabricante.
Base del preenfriador RU1101A · mortero superior de 50 mm | Mortero HA-35 de alta resistencia sin retracción | 4.26237 | 2.72431 | 0.05 | 286.25 | 286.3 | 18.22 | 0.44 | {"documentId":"LHD2609-JG00100-20260904","title":"Cimentaciones de equipos y pedestales del fabricante · revisión recibida 04/09/2026","date":"2026-09-04","sheet":"2–2","fileName":"LHD2609-JG00100_20260904.dwg","revisionCaveat":"Fecha de revisión tomada del nombre recibido; cajetines internos mantienen 02/07/2026 y algunos textos de plantilla.","sourceFileSha256":"b42eb027b7bc0b14c38d1d13514f4899b58a732aa8d0ba2ccf10fa2fc3192890"} | {"name":"Mortero HA-35 de alta resistencia sin retracción","status":"documentado","source":"Capa superior de 50 mm expresada en las secciones del fabricante"} | {"documented":[{"label":"Extensión local X","value":4.0,"unit":"m","source":"2934/2402, 28CEA","status":"derivada del contorno CAD"},{"label":"Extensión local Y","value":2.2,"unit":"m","source":"2934/2402, 28CEA","status":"derivada del contorno CAD"},{"label":"Cota inferior relativa adoptada","value":0.15000000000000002,"unit":"m","source":"2–2","status":"interpretación con conflicto conservado"},{"label":"Cota superior relativa adoptada","value":0.2,"unit":"m","source":"2–2","status":"documentada / separación por material"}],"geometry":[{"label":"Extensión de la malla en X","value":4.262372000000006,"unit":"m","source":"Geometría releída del IFC; datum absoluto de proceso provisional","status":"derivado"},{"label":"Extensión de la malla en Y","value":2.7243139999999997,"unit":"m","source":"Geometría releída del IFC; datum absoluto de proceso provisional","status":"derivado"},{"label":"Extensión de la malla en Z","value":0.050000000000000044,"unit":"m","source":"Geometría releída del IFC; datum absoluto de proceso provisional","status":"derivado"},{"label":"Cota inferior de visualización","value":286.25,"unit":"m","source":"Geometría releída del IFC; datum absoluto de proceso provisional","status":"derivado"},{"label":"Cota superior de visualización","value":286.3,"unit":"m","source":"Geometría releída del IFC; datum absoluto de proceso provisional","status":"derivado"}]} | ["La etiqueta inferior indica −3,000 m, pero la sección y su cadena 200 + 1000 = 1200 mm indican −1,000 m. Se adopta −1,000 m para la geometría; pendiente de aclaración del fabricante."] | {"Cota inferior relativa (m)":0.15000000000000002,"Cota superior relativa (m)":0.2,"Cero absoluto de visualización (m)":286.1,"Estado del cero absoluto":"Provisional","Criterio":"Las cotas relativas proceden del dibujo; la equivalencia absoluta no está confirmada."} | F-RU1101A | ["RU1101A"] | [] | 2–2 | ["2934/2402","28CEA"] | F-RU1101A/Base del preenfriador RU1101A · mortero superior de 50 mm | {"boundingBoxM":{"min":[47.013935,63.817207,1.25],"max":[51.276307,66.541521,1.3]},"extentsM":[4.262372,2.724314,0.05],"meshSurfaceM2":18.220003,"meshVolumeM3":0.44,"closedSolid":true,"basis":"Magnitudes de las mallas representadas, no cantidades certificadas de obra, compra o fabricación. Las partes pueden compartir superficies; no se suman como un despiece de materiales."} | {"profileId":"grout_ha35","name":"Grout HA-35 sin retracción","materialName":"Mortero HA-35 de alta resistencia sin retracción","physicalMaterialStatus":"documentado","physicalMaterialSource":"Capa superior de 50 mm expresada en las secciones del fabricante","appearanceStatus":"criterio_visual","appearanceBasis":"Interpretación visual del material documental; el acabado, tono y parámetros PBR no son una especificación contractual.","note":"La apariencia gráfica no modifica ni confirma la especificación física del material."} | {"elementId":"found_0904_1c12b72639217c","ifcGuid":"1QrWNXxAHHlAF_yyye_yoO","ifcClass":"IfcSlab","buildingId":"process_plant","buildingName":"Zona de separación de aire","sourceDocumentId":"LHD2609-JG00100-20260904","sourceRepresentationKind":"foundation"} | {"profileId":"grout_ha35","name":"Grout HA-35 sin retracción","status":"criterio_visual","basis":"Interpretación visual del material documental; el acabado, tono y parámetros PBR no son una especificación contractual.","physicalMaterialUnchanged":true} | RU1101A | 2934/2402, 28CEA | Mortero HA-35 de alta resistencia sin retracción | 0.15 | 0.2 | 8.8 | 0.44 | Sección y contornos del fabricante; incidencias conservadas | Grout HA-35 sin retracción | found_0904_1c12b72639217c | documentado | Capa superior de 50 mm expresada en las secciones del fabricante | 4 | 2.2 | grout_ha35 | [0.792157,0.776471,0.721569] | 0.94 | La etiqueta inferior indica −3,000 m, pero la sección y su cadena 200 + 1000 = 1200 mm indican −1,000 m. Se adopta −1,000 m para la geometría; pendiente de aclaración del fabricante.
Base del preenfriador RU1101B · capa de limpieza | Hormigón de limpieza HA-20 | 4.48775 | 2.94969 | 0.1 | 285 | 285.1 | 21.48 | 1.008 | {"documentId":"LHD2609-JG00100-20260904","title":"Cimentaciones de equipos y pedestales del fabricante · revisión recibida 04/09/2026","date":"2026-09-04","sheet":"2–2","fileName":"LHD2609-JG00100_20260904.dwg","revisionCaveat":"Fecha de revisión tomada del nombre recibido; cajetines internos mantienen 02/07/2026 y algunos textos de plantilla.","sourceFileSha256":"b42eb027b7bc0b14c38d1d13514f4899b58a732aa8d0ba2ccf10fa2fc3192890"} | {"name":"Hormigón de limpieza HA-20","status":"documentado","source":"Secciones del fabricante: capa de limpieza de 100 mm; nota 2CED5"} | {"documented":[{"label":"Extensión local X","value":4.2,"unit":"m","source":"2933/2402, 28CEA","status":"derivada del contorno CAD"},{"label":"Extensión local Y","value":2.4,"unit":"m","source":"2933/2402, 28CEA","status":"derivada del contorno CAD"},{"label":"Cota inferior relativa adoptada","value":-1.1,"unit":"m","source":"2–2","status":"interpretación con conflicto conservado"},{"label":"Cota superior relativa adoptada","value":-1,"unit":"m","source":"2–2","status":"documentada / separación por material"}],"geometry":[{"label":"Extensión de la malla en X","value":4.487749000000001,"unit":"m","source":"Geometría releída del IFC; datum absoluto de proceso provisional","status":"derivado"},{"label":"Extensión de la malla en Y","value":2.949690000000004,"unit":"m","source":"Geometría releída del IFC; datum absoluto de proceso provisional","status":"derivado"},{"label":"Extensión de la malla en Z","value":0.1,"unit":"m","source":"Geometría releída del IFC; datum absoluto de proceso provisional","status":"derivado"},{"label":"Cota inferior de visualización","value":285.0,"unit":"m","source":"Geometría releída del IFC; datum absoluto de proceso provisional","status":"derivado"},{"label":"Cota superior de visualización","value":285.1,"unit":"m","source":"Geometría releída del IFC; datum absoluto de proceso provisional","status":"derivado"}]} | ["La etiqueta inferior indica −3,000 m, pero la sección y su cadena 200 + 1000 = 1200 mm indican −1,000 m. Se adopta −1,000 m para la geometría; pendiente de aclaración del fabricante."] | {"Cota inferior relativa (m)":-1.1,"Cota superior relativa (m)":-1,"Cero absoluto de visualización (m)":286.1,"Estado del cero absoluto":"Provisional","Criterio":"Las cotas relativas proceden del dibujo; la equivalencia absoluta no está confirmada."} | F-RU1101B | ["RU1101B"] | [] | 2–2 | ["2933/2402","28CEA"] | F-RU1101B/Base del preenfriador RU1101B · capa de limpieza | {"boundingBoxM":{"min":[53.241603,62.832814,0.0],"max":[57.729352,65.782504,0.1]},"extentsM":[4.487749,2.94969,0.1],"meshSurfaceM2":21.48,"meshVolumeM3":1.008,"closedSolid":true,"basis":"Magnitudes de las mallas representadas, no cantidades certificadas de obra, compra o fabricación. Las partes pueden compartir superficies; no se suman como un despiece de materiales."} | {"profileId":"concrete_ha20","name":"Hormigón de limpieza HA-20","materialName":"Hormigón de limpieza HA-20","physicalMaterialStatus":"documentado","physicalMaterialSource":"Secciones del fabricante: capa de limpieza de 100 mm; nota 2CED5","appearanceStatus":"criterio_visual","appearanceBasis":"Interpretación visual del material documental; el acabado, tono y parámetros PBR no son una especificación contractual.","note":"La apariencia gráfica no modifica ni confirma la especificación física del material."} | {"elementId":"found_0904_6c005dd8549efe","ifcGuid":"3RutyhuZ9IPwPx4syd9F2c","ifcClass":"IfcSlab","buildingId":"process_plant","buildingName":"Zona de separación de aire","sourceDocumentId":"LHD2609-JG00100-20260904","sourceRepresentationKind":"foundation"} | {"profileId":"concrete_ha20","name":"Hormigón de limpieza HA-20","status":"criterio_visual","basis":"Interpretación visual del material documental; el acabado, tono y parámetros PBR no son una especificación contractual.","physicalMaterialUnchanged":true} | RU1101B | 2933/2402, 28CEA | Hormigón de limpieza HA-20 | -1.1 | -1 | 10.08 | 1.008 | Sección y contornos del fabricante; incidencias conservadas | Hormigón de limpieza HA-20 | found_0904_6c005dd8549efe | documentado | Secciones del fabricante: capa de limpieza de 100 mm; nota 2CED5 | 4.2 | 2.4 | concrete_ha20 | [0.721569,0.709804,0.658824] | 0.98 | La etiqueta inferior indica −3,000 m, pero la sección y su cadena 200 + 1000 = 1200 mm indican −1,000 m. Se adopta −1,000 m para la geometría; pendiente de aclaración del fabricante.
Base del preenfriador RU1101B · mortero superior de 50 mm | Mortero HA-35 de alta resistencia sin retracción | 4.26237 | 2.72431 | 0.05 | 286.25 | 286.3 | 18.22 | 0.44 | {"documentId":"LHD2609-JG00100-20260904","title":"Cimentaciones de equipos y pedestales del fabricante · revisión recibida 04/09/2026","date":"2026-09-04","sheet":"2–2","fileName":"LHD2609-JG00100_20260904.dwg","revisionCaveat":"Fecha de revisión tomada del nombre recibido; cajetines internos mantienen 02/07/2026 y algunos textos de plantilla.","sourceFileSha256":"b42eb027b7bc0b14c38d1d13514f4899b58a732aa8d0ba2ccf10fa2fc3192890"} | {"name":"Mortero HA-35 de alta resistencia sin retracción","status":"documentado","source":"Capa superior de 50 mm expresada en las secciones del fabricante"} | {"documented":[{"label":"Extensión local X","value":4.0,"unit":"m","source":"2933/2402, 28CEA","status":"derivada del contorno CAD"},{"label":"Extensión local Y","value":2.2,"unit":"m","source":"2933/2402, 28CEA","status":"derivada del contorno CAD"},{"label":"Cota inferior relativa adoptada","value":0.15000000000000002,"unit":"m","source":"2–2","status":"interpretación con conflicto conservado"},{"label":"Cota superior relativa adoptada","value":0.2,"unit":"m","source":"2–2","status":"documentada / separación por material"}],"geometry":[{"label":"Extensión de la malla en X","value":4.262371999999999,"unit":"m","source":"Geometría releída del IFC; datum absoluto de proceso provisional","status":"derivado"},{"label":"Extensión de la malla en Y","value":2.7243139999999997,"unit":"m","source":"Geometría releída del IFC; datum absoluto de proceso provisional","status":"derivado"},{"label":"Extensión de la malla en Z","value":0.050000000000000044,"unit":"m","source":"Geometría releída del IFC; datum absoluto de proceso provisional","status":"derivado"},{"label":"Cota inferior de visualización","value":286.25,"unit":"m","source":"Geometría releída del IFC; datum absoluto de proceso provisional","status":"derivado"},{"label":"Cota superior de visualización","value":286.3,"unit":"m","source":"Geometría releída del IFC; datum absoluto de proceso provisional","status":"derivado"}]} | ["La etiqueta inferior indica −3,000 m, pero la sección y su cadena 200 + 1000 = 1200 mm indican −1,000 m. Se adopta −1,000 m para la geometría; pendiente de aclaración del fabricante."] | {"Cota inferior relativa (m)":0.15000000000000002,"Cota superior relativa (m)":0.2,"Cero absoluto de visualización (m)":286.1,"Estado del cero absoluto":"Provisional","Criterio":"Las cotas relativas proceden del dibujo; la equivalencia absoluta no está confirmada."} | F-RU1101B | ["RU1101B"] | [] | 2–2 | ["2933/2402","28CEA"] | F-RU1101B/Base del preenfriador RU1101B · mortero superior de 50 mm | {"boundingBoxM":{"min":[53.354292,62.945502,1.25],"max":[57.616664,65.669816,1.3]},"extentsM":[4.262372,2.724314,0.05],"meshSurfaceM2":18.220001,"meshVolumeM3":0.44,"closedSolid":true,"basis":"Magnitudes de las mallas representadas, no cantidades certificadas de obra, compra o fabricación. Las partes pueden compartir superficies; no se suman como un despiece de materiales."} | {"profileId":"grout_ha35","name":"Grout HA-35 sin retracción","materialName":"Mortero HA-35 de alta resistencia sin retracción","physicalMaterialStatus":"documentado","physicalMaterialSource":"Capa superior de 50 mm expresada en las secciones del fabricante","appearanceStatus":"criterio_visual","appearanceBasis":"Interpretación visual del material documental; el acabado, tono y parámetros PBR no son una especificación contractual.","note":"La apariencia gráfica no modifica ni confirma la especificación física del material."} | {"elementId":"found_0904_f4a89c716abc6c","ifcGuid":"04NerwKz9QXeDHhZDDm6Tz","ifcClass":"IfcSlab","buildingId":"process_plant","buildingName":"Zona de separación de aire","sourceDocumentId":"LHD2609-JG00100-20260904","sourceRepresentationKind":"foundation"} | {"profileId":"grout_ha35","name":"Grout HA-35 sin retracción","status":"criterio_visual","basis":"Interpretación visual del material documental; el acabado, tono y parámetros PBR no son una especificación contractual.","physicalMaterialUnchanged":true} | RU1101B | 2933/2402, 28CEA | Mortero HA-35 de alta resistencia sin retracción | 0.15 | 0.2 | 8.8 | 0.44 | Sección y contornos del fabricante; incidencias conservadas | Grout HA-35 sin retracción | found_0904_f4a89c716abc6c | documentado | Capa superior de 50 mm expresada en las secciones del fabricante | 4 | 2.2 | grout_ha35 | [0.792157,0.776471,0.721569] | 0.94 | La etiqueta inferior indica −3,000 m, pero la sección y su cadena 200 + 1000 = 1200 mm indican −1,000 m. Se adopta −1,000 m para la geometría; pendiente de aclaración del fabricante.
Base del preenfriador RU1101C · capa de limpieza | Hormigón de limpieza HA-20 | 4.48775 | 2.94969 | 0.1 | 285 | 285.1 | 21.48 | 1.008 | {"documentId":"LHD2609-JG00100-20260904","title":"Cimentaciones de equipos y pedestales del fabricante · revisión recibida 04/09/2026","date":"2026-09-04","sheet":"2–2","fileName":"LHD2609-JG00100_20260904.dwg","revisionCaveat":"Fecha de revisión tomada del nombre recibido; cajetines internos mantienen 02/07/2026 y algunos textos de plantilla.","sourceFileSha256":"b42eb027b7bc0b14c38d1d13514f4899b58a732aa8d0ba2ccf10fa2fc3192890"} | {"name":"Hormigón de limpieza HA-20","status":"documentado","source":"Secciones del fabricante: capa de limpieza de 100 mm; nota 2CED5"} | {"documented":[{"label":"Extensión local X","value":4.2,"unit":"m","source":"23FF/2402, 28CEA","status":"derivada del contorno CAD"},{"label":"Extensión local Y","value":2.4,"unit":"m","source":"23FF/2402, 28CEA","status":"derivada del contorno CAD"},{"label":"Cota inferior relativa adoptada","value":-1.1,"unit":"m","source":"2–2","status":"interpretación con conflicto conservado"},{"label":"Cota superior relativa adoptada","value":-1,"unit":"m","source":"2–2","status":"documentada / separación por material"}],"geometry":[{"label":"Extensión de la malla en X","value":4.487749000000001,"unit":"m","source":"Geometría releída del IFC; datum absoluto de proceso provisional","status":"derivado"},{"label":"Extensión de la malla en Y","value":2.949689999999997,"unit":"m","source":"Geometría releída del IFC; datum absoluto de proceso provisional","status":"derivado"},{"label":"Extensión de la malla en Z","value":0.1,"unit":"m","source":"Geometría releída del IFC; datum absoluto de proceso provisional","status":"derivado"},{"label":"Cota inferior de visualización","value":285.0,"unit":"m","source":"Geometría releída del IFC; datum absoluto de proceso provisional","status":"derivado"},{"label":"Cota superior de visualización","value":285.1,"unit":"m","source":"Geometría releída del IFC; datum absoluto de proceso provisional","status":"derivado"}]} | ["La etiqueta inferior indica −3,000 m, pero la sección y su cadena 200 + 1000 = 1200 mm indican −1,000 m. Se adopta −1,000 m para la geometría; pendiente de aclaración del fabricante."] | {"Cota inferior relativa (m)":-1.1,"Cota superior relativa (m)":-1,"Cero absoluto de visualización (m)":286.1,"Estado del cero absoluto":"Provisional","Criterio":"Las cotas relativas proceden del dibujo; la equivalencia absoluta no está confirmada."} | F-RU1101C | ["RU1101C"] | [] | 2–2 | ["23FF/2402","28CEA"] | F-RU1101C/Base del preenfriador RU1101C · capa de limpieza | {"boundingBoxM":{"min":[59.581961,61.961109,0.0],"max":[64.06971,64.910799,0.1]},"extentsM":[4.487749,2.94969,0.1],"meshSurfaceM2":21.48,"meshVolumeM3":1.008,"closedSolid":true,"basis":"Magnitudes de las mallas representadas, no cantidades certificadas de obra, compra o fabricación. Las partes pueden compartir superficies; no se suman como un despiece de materiales."} | {"profileId":"concrete_ha20","name":"Hormigón de limpieza HA-20","materialName":"Hormigón de limpieza HA-20","physicalMaterialStatus":"documentado","physicalMaterialSource":"Secciones del fabricante: capa de limpieza de 100 mm; nota 2CED5","appearanceStatus":"criterio_visual","appearanceBasis":"Interpretación visual del material documental; el acabado, tono y parámetros PBR no son una especificación contractual.","note":"La apariencia gráfica no modifica ni confirma la especificación física del material."} | {"elementId":"found_0904_57e3a3d649e27e","ifcGuid":"2UAuglA1TJshLoDdLb3qaM","ifcClass":"IfcSlab","buildingId":"process_plant","buildingName":"Zona de separación de aire","sourceDocumentId":"LHD2609-JG00100-20260904","sourceRepresentationKind":"foundation"} | {"profileId":"concrete_ha20","name":"Hormigón de limpieza HA-20","status":"criterio_visual","basis":"Interpretación visual del material documental; el acabado, tono y parámetros PBR no son una especificación contractual.","physicalMaterialUnchanged":true} | RU1101C | 23FF/2402, 28CEA | Hormigón de limpieza HA-20 | -1.1 | -1 | 10.08 | 1.008 | Sección y contornos del fabricante; incidencias conservadas | Hormigón de limpieza HA-20 | found_0904_57e3a3d649e27e | documentado | Secciones del fabricante: capa de limpieza de 100 mm; nota 2CED5 | 4.2 | 2.4 | concrete_ha20 | [0.721569,0.709804,0.658824] | 0.98 | La etiqueta inferior indica −3,000 m, pero la sección y su cadena 200 + 1000 = 1200 mm indican −1,000 m. Se adopta −1,000 m para la geometría; pendiente de aclaración del fabricante.
Base del preenfriador RU1101C · mortero superior de 50 mm | Mortero HA-35 de alta resistencia sin retracción | 4.26237 | 2.72431 | 0.05 | 286.25 | 286.3 | 18.22 | 0.44 | {"documentId":"LHD2609-JG00100-20260904","title":"Cimentaciones de equipos y pedestales del fabricante · revisión recibida 04/09/2026","date":"2026-09-04","sheet":"2–2","fileName":"LHD2609-JG00100_20260904.dwg","revisionCaveat":"Fecha de revisión tomada del nombre recibido; cajetines internos mantienen 02/07/2026 y algunos textos de plantilla.","sourceFileSha256":"b42eb027b7bc0b14c38d1d13514f4899b58a732aa8d0ba2ccf10fa2fc3192890"} | {"name":"Mortero HA-35 de alta resistencia sin retracción","status":"documentado","source":"Capa superior de 50 mm expresada en las secciones del fabricante"} | {"documented":[{"label":"Extensión local X","value":4.0,"unit":"m","source":"23FF/2402, 28CEA","status":"derivada del contorno CAD"},{"label":"Extensión local Y","value":2.2,"unit":"m","source":"23FF/2402, 28CEA","status":"derivada del contorno CAD"},{"label":"Cota inferior relativa adoptada","value":0.15000000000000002,"unit":"m","source":"2–2","status":"interpretación con conflicto conservado"},{"label":"Cota superior relativa adoptada","value":0.2,"unit":"m","source":"2–2","status":"documentada / separación por material"}],"geometry":[{"label":"Extensión de la malla en X","value":4.262371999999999,"unit":"m","source":"Geometría releída del IFC; datum absoluto de proceso provisional","status":"derivado"},{"label":"Extensión de la malla en Y","value":2.724314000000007,"unit":"m","source":"Geometría releída del IFC; datum absoluto de proceso provisional","status":"derivado"},{"label":"Extensión de la malla en Z","value":0.050000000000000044,"unit":"m","source":"Geometría releída del IFC; datum absoluto de proceso provisional","status":"derivado"},{"label":"Cota inferior de visualización","value":286.25,"unit":"m","source":"Geometría releída del IFC; datum absoluto de proceso provisional","status":"derivado"},{"label":"Cota superior de visualización","value":286.3,"unit":"m","source":"Geometría releída del IFC; datum absoluto de proceso provisional","status":"derivado"}]} | ["La etiqueta inferior indica −3,000 m, pero la sección y su cadena 200 + 1000 = 1200 mm indican −1,000 m. Se adopta −1,000 m para la geometría; pendiente de aclaración del fabricante."] | {"Cota inferior relativa (m)":0.15000000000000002,"Cota superior relativa (m)":0.2,"Cero absoluto de visualización (m)":286.1,"Estado del cero absoluto":"Provisional","Criterio":"Las cotas relativas proceden del dibujo; la equivalencia absoluta no está confirmada."} | F-RU1101C | ["RU1101C"] | [] | 2–2 | ["23FF/2402","28CEA"] | F-RU1101C/Base del preenfriador RU1101C · mortero superior de 50 mm | {"boundingBoxM":{"min":[59.694649,62.073797,1.25],"max":[63.957021,64.798111,1.3]},"extentsM":[4.262372,2.724314,0.05],"meshSurfaceM2":18.220001,"meshVolumeM3":0.44,"closedSolid":true,"basis":"Magnitudes de las mallas representadas, no cantidades certificadas de obra, compra o fabricación. Las partes pueden compartir superficies; no se suman como un despiece de materiales."} | {"profileId":"grout_ha35","name":"Grout HA-35 sin retracción","materialName":"Mortero HA-35 de alta resistencia sin retracción","physicalMaterialStatus":"documentado","physicalMaterialSource":"Capa superior de 50 mm expresada en las secciones del fabricante","appearanceStatus":"criterio_visual","appearanceBasis":"Interpretación visual del material documental; el acabado, tono y parámetros PBR no son una especificación contractual.","note":"La apariencia gráfica no modifica ni confirma la especificación física del material."} | {"elementId":"found_0904_472a35ad377965","ifcGuid":"1J9jyVSDLGxezGJATDvCeo","ifcClass":"IfcSlab","buildingId":"process_plant","buildingName":"Zona de separación de aire","sourceDocumentId":"LHD2609-JG00100-20260904","sourceRepresentationKind":"foundation"} | {"profileId":"grout_ha35","name":"Grout HA-35 sin retracción","status":"criterio_visual","basis":"Interpretación visual del material documental; el acabado, tono y parámetros PBR no son una especificación contractual.","physicalMaterialUnchanged":true} | RU1101C | 23FF/2402, 28CEA | Mortero HA-35 de alta resistencia sin retracción | 0.15 | 0.2 | 8.8 | 0.44 | Sección y contornos del fabricante; incidencias conservadas | Grout HA-35 sin retracción | found_0904_472a35ad377965 | documentado | Capa superior de 50 mm expresada en las secciones del fabricante | 4 | 2.2 | grout_ha35 | [0.792157,0.776471,0.721569] | 0.94 | La etiqueta inferior indica −3,000 m, pero la sección y su cadena 200 + 1000 = 1200 mm indican −1,000 m. Se adopta −1,000 m para la geometría; pendiente de aclaración del fabricante.
Cimentación de purificación · capa de limpieza | Hormigón de limpieza HA-20 | 11.4509 | 9.05838 | 0.1 | 285 | 285.1 | 165.34 | 8.085 | {"documentId":"LHD2609-JG00100-20260904","title":"Cimentaciones de equipos y pedestales del fabricante · revisión recibida 04/09/2026","date":"2026-09-04","sheet":"3–3","fileName":"LHD2609-JG00100_20260904.dwg","revisionCaveat":"Fecha de revisión tomada del nombre recibido; cajetines internos mantienen 02/07/2026 y algunos textos de plantilla.","sourceFileSha256":"b42eb027b7bc0b14c38d1d13514f4899b58a732aa8d0ba2ccf10fa2fc3192890"} | {"name":"Hormigón de limpieza HA-20","status":"documentado","source":"Secciones del fabricante: capa de limpieza de 100 mm; nota 2CED5"} | {"documented":[{"label":"Extensión local X","value":10.5,"unit":"m","source":"283A, 28D14, 283A/F525","status":"derivada del contorno CAD"},{"label":"Extensión local Y","value":7.7,"unit":"m","source":"283A, 28D14, 283A/F525","status":"derivada del contorno CAD"},{"label":"Cota inferior relativa adoptada","value":-1.1,"unit":"m","source":"3–3","status":"interpretación con conflicto conservado"},{"label":"Cota superior relativa adoptada","value":-1,"unit":"m","source":"3–3","status":"documentada / separación por material"}],"geometry":[{"label":"Extensión de la malla en X","value":11.450918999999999,"unit":"m","source":"Geometría releída del IFC; datum absoluto de proceso provisional","status":"derivado"},{"label":"Extensión de la malla en Y","value":9.058383,"unit":"m","source":"Geometría releída del IFC; datum absoluto de proceso provisional","status":"derivado"},{"label":"Extensión de la malla en Z","value":0.1,"unit":"m","source":"Geometría releída del IFC; datum absoluto de proceso provisional","status":"derivado"},{"label":"Cota inferior de visualización","value":285.0,"unit":"m","source":"Geometría releída del IFC; datum absoluto de proceso provisional","status":"derivado"},{"label":"Cota superior de visualización","value":285.1,"unit":"m","source":"Geometría releída del IFC; datum absoluto de proceso provisional","status":"derivado"}]} | ["Los símbolos simplificados del plano general de apoyos no definen el alzado de los recipientes."] | {"Cota inferior relativa (m)":-1.1,"Cota superior relativa (m)":-1,"Cero absoluto de visualización (m)":286.1,"Estado del cero absoluto":"Provisional","Criterio":"Las cotas relativas proceden del dibujo; la equivalencia absoluta no está confirmada."} | F-PPU | ["PPU-A-PLAN","PPU-B-PLAN","HEATER-PLAN","PPU-VALVE-SKID"] | [] | 3–3 | ["283A","28D14","283A/F525"] | F-PPU/Cimentación de purificación · capa de limpieza | {"boundingBoxM":{"min":[48.167596,53.335317,0.0],"max":[59.618515,62.3937,0.1]},"extentsM":[11.450919,9.058383,0.1],"meshSurfaceM2":165.339998,"meshVolumeM3":8.085,"closedSolid":true,"basis":"Magnitudes de las mallas representadas, no cantidades certificadas de obra, compra o fabricación. Las partes pueden compartir superficies; no se suman como un despiece de materiales."} | {"profileId":"concrete_ha20","name":"Hormigón de limpieza HA-20","materialName":"Hormigón de limpieza HA-20","physicalMaterialStatus":"documentado","physicalMaterialSource":"Secciones del fabricante: capa de limpieza de 100 mm; nota 2CED5","appearanceStatus":"criterio_visual","appearanceBasis":"Interpretación visual del material documental; el acabado, tono y parámetros PBR no son una especificación contractual.","note":"La apariencia gráfica no modifica ni confirma la especificación física del material."} | {"elementId":"found_0904_c3bd5e0d38836a","ifcGuid":"36rCR5ZTfVT9sHvKPmhujn","ifcClass":"IfcSlab","buildingId":"process_plant","buildingName":"Zona de separación de aire","sourceDocumentId":"LHD2609-JG00100-20260904","sourceRepresentationKind":"foundation"} | {"profileId":"concrete_ha20","name":"Hormigón de limpieza HA-20","status":"criterio_visual","basis":"Interpretación visual del material documental; el acabado, tono y parámetros PBR no son una especificación contractual.","physicalMaterialUnchanged":true} | PPU-A-PLAN, PPU-B-PLAN, HEATER-PLAN, PPU-VALVE-SKID | 283A, 28D14, 283A/F525 | Hormigón de limpieza HA-20 | -1.1 | -1 | 80.85 | 8.085 | Sección y contornos del fabricante; incidencias conservadas | Hormigón de limpieza HA-20 | found_0904_c3bd5e0d38836a | documentado | Secciones del fabricante: capa de limpieza de 100 mm; nota 2CED5 | 10.5 | 7.7 | concrete_ha20 | [0.721569,0.709804,0.658824] | 0.98 | Los símbolos simplificados del plano general de apoyos no definen el alzado de los recipientes.
Cimentación de purificación · mortero superior de 50 mm | Mortero HA-35 de alta resistencia sin retracción | 11.2255 | 8.83301 | 0.05 | 286.15 | 286.2 | 156.28 | 3.8625 | {"documentId":"LHD2609-JG00100-20260904","title":"Cimentaciones de equipos y pedestales del fabricante · revisión recibida 04/09/2026","date":"2026-09-04","sheet":"3–3","fileName":"LHD2609-JG00100_20260904.dwg","revisionCaveat":"Fecha de revisión tomada del nombre recibido; cajetines internos mantienen 02/07/2026 y algunos textos de plantilla.","sourceFileSha256":"b42eb027b7bc0b14c38d1d13514f4899b58a732aa8d0ba2ccf10fa2fc3192890"} | {"name":"Mortero HA-35 de alta resistencia sin retracción","status":"documentado","source":"Capa superior de 50 mm expresada en las secciones del fabricante"} | {"documented":[{"label":"Extensión local X","value":10.3,"unit":"m","source":"283A, 28D14, 283A/F525","status":"derivada del contorno CAD"},{"label":"Extensión local Y","value":7.5,"unit":"m","source":"283A, 28D14, 283A/F525","status":"derivada del contorno CAD"},{"label":"Cota inferior relativa adoptada","value":0.05,"unit":"m","source":"3–3","status":"interpretación con conflicto conservado"},{"label":"Cota superior relativa adoptada","value":0.1,"unit":"m","source":"3–3","status":"documentada / separación por material"}],"geometry":[{"label":"Extensión de la malla en X","value":11.225541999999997,"unit":"m","source":"Geometría releída del IFC; datum absoluto de proceso provisional","status":"derivado"},{"label":"Extensión de la malla en Y","value":8.833006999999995,"unit":"m","source":"Geometría releída del IFC; datum absoluto de proceso provisional","status":"derivado"},{"label":"Extensión de la malla en Z","value":0.050000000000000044,"unit":"m","source":"Geometría releída del IFC; datum absoluto de proceso provisional","status":"derivado"},{"label":"Cota inferior de visualización","value":286.15,"unit":"m","source":"Geometría releída del IFC; datum absoluto de proceso provisional","status":"derivado"},{"label":"Cota superior de visualización","value":286.2,"unit":"m","source":"Geometría releída del IFC; datum absoluto de proceso provisional","status":"derivado"}]} | ["Los símbolos simplificados del plano general de apoyos no definen el alzado de los recipientes."] | {"Cota inferior relativa (m)":0.05,"Cota superior relativa (m)":0.1,"Cero absoluto de visualización (m)":286.1,"Estado del cero absoluto":"Provisional","Criterio":"Las cotas relativas proceden del dibujo; la equivalencia absoluta no está confirmada."} | F-PPU | ["PPU-A-PLAN","PPU-B-PLAN","HEATER-PLAN","PPU-VALVE-SKID"] | [] | 3–3 | ["283A","28D14","283A/F525"] | F-PPU/Cimentación de purificación · mortero superior de 50 mm | {"boundingBoxM":{"min":[48.280284,53.448005,1.15],"max":[59.505826,62.281012,1.2]},"extentsM":[11.225542,8.833007,0.05],"meshSurfaceM2":156.280008,"meshVolumeM3":3.8625,"closedSolid":true,"basis":"Magnitudes de las mallas representadas, no cantidades certificadas de obra, compra o fabricación. Las partes pueden compartir superficies; no se suman como un despiece de materiales."} | {"profileId":"grout_ha35","name":"Grout HA-35 sin retracción","materialName":"Mortero HA-35 de alta resistencia sin retracción","physicalMaterialStatus":"documentado","physicalMaterialSource":"Capa superior de 50 mm expresada en las secciones del fabricante","appearanceStatus":"criterio_visual","appearanceBasis":"Interpretación visual del material documental; el acabado, tono y parámetros PBR no son una especificación contractual.","note":"La apariencia gráfica no modifica ni confirma la especificación física del material."} | {"elementId":"found_0904_bc40ce234e571f","ifcGuid":"06YZ2j1l5VCBWEWiuDbZqC","ifcClass":"IfcSlab","buildingId":"process_plant","buildingName":"Zona de separación de aire","sourceDocumentId":"LHD2609-JG00100-20260904","sourceRepresentationKind":"foundation"} | {"profileId":"grout_ha35","name":"Grout HA-35 sin retracción","status":"criterio_visual","basis":"Interpretación visual del material documental; el acabado, tono y parámetros PBR no son una especificación contractual.","physicalMaterialUnchanged":true} | PPU-A-PLAN, PPU-B-PLAN, HEATER-PLAN, PPU-VALVE-SKID | 283A, 28D14, 283A/F525 | Mortero HA-35 de alta resistencia sin retracción | 0.05 | 0.1 | 77.25 | 3.8625 | Sección y contornos del fabricante; incidencias conservadas | Grout HA-35 sin retracción | found_0904_bc40ce234e571f | documentado | Capa superior de 50 mm expresada en las secciones del fabricante | 10.3 | 7.5 | grout_ha35 | [0.792157,0.776471,0.721569] | 0.94 | Los símbolos simplificados del plano general de apoyos no definen el alzado de los recipientes.
Cimentación de las cajas frías · capa de limpieza | Hormigón de limpieza HA-20 | 12.7164 | 15.8582 | 0.1 | 284.5 | 284.6 | 293.984 | 14.4355 | {"documentId":"LHD2609-JG00100-20260904","title":"Cimentaciones de equipos y pedestales del fabricante · revisión recibida 04/09/2026","date":"2026-09-04","sheet":"4–4 / 4a–4a","fileName":"LHD2609-JG00100_20260904.dwg","revisionCaveat":"Fecha de revisión tomada del nombre recibido; cajetines internos mantienen 02/07/2026 y algunos textos de plantilla.","sourceFileSha256":"b42eb027b7bc0b14c38d1d13514f4899b58a732aa8d0ba2ccf10fa2fc3192890"} | {"name":"Hormigón de limpieza HA-20","status":"documentado","source":"Secciones del fabricante: capa de limpieza de 100 mm; nota 2CED5"} | {"documented":[{"label":"Extensión local X","value":11.49,"unit":"m","source":"240F/2420, 240F/250C, 240F/250D, 240F/250E, 240F/250F, 240F/2510, 1FCF3","status":"derivada del contorno CAD"},{"label":"Extensión local Y","value":14.88,"unit":"m","source":"240F/2420, 240F/250C, 240F/250D, 240F/250E, 240F/250F, 240F/2510, 1FCF3","status":"derivada del contorno CAD"},{"label":"Cota inferior relativa adoptada","value":-1.6,"unit":"m","source":"4–4 / 4a–4a","status":"interpretación con conflicto conservado"},{"label":"Cota superior relativa adoptada","value":-1.5,"unit":"m","source":"4–4 / 4a–4a","status":"documentada / separación por material"}],"geometry":[{"label":"Extensión de la malla en X","value":12.716359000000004,"unit":"m","source":"Geometría releída del IFC; datum absoluto de proceso provisional","status":"derivado"},{"label":"Extensión de la malla en Y","value":15.858202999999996,"unit":"m","source":"Geometría releída del IFC; datum absoluto de proceso provisional","status":"derivado"},{"label":"Extensión de la malla en Z","value":0.09999999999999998,"unit":"m","source":"Geometría releída del IFC; datum absoluto de proceso provisional","status":"derivado"},{"label":"Cota inferior de visualización","value":284.5,"unit":"m","source":"Geometría releída del IFC; datum absoluto de proceso provisional","status":"derivado"},{"label":"Cota superior de visualización","value":284.6,"unit":"m","source":"Geometría releída del IFC; datum absoluto de proceso provisional","status":"derivado"}]} | ["Sección 4–4: etiqueta inferior −1,000 m frente a 1500 mm. Sección 4a–4a y espesor1500 mm: −1,500 m. Se adopta −1,500 m; conflicto pendiente."] | {"Cota inferior relativa (m)":-1.6,"Cota superior relativa (m)":-1.5,"Cero absoluto de visualización (m)":286.1,"Estado del cero absoluto":"Provisional","Criterio":"Las cotas relativas proceden del dibujo; la equivalencia absoluta no está confirmada."} | F-CB | ["CB-MAIN","CB-HX-PLAN","CB-EXP-N-PLAN","CB-EXP-W-PLAN"] | [] | 4–4 / 4a–4a | ["240F/2420","240F/250C","240F/250D","240F/250E","240F/250F","240F/2510","1FCF3"] | F-CB/Cimentación de las cajas frías · capa de limpieza | {"boundingBoxM":{"min":[48.863831,35.197299,-0.5],"max":[61.58019,51.055502,-0.4]},"extentsM":[12.716359,15.858203,0.1],"meshSurfaceM2":293.984198,"meshVolumeM3":14.43551,"closedSolid":true,"basis":"Magnitudes de las mallas representadas, no cantidades certificadas de obra, compra o fabricación. Las partes pueden compartir superficies; no se suman como un despiece de materiales."} | {"profileId":"concrete_ha20","name":"Hormigón de limpieza HA-20","materialName":"Hormigón de limpieza HA-20","physicalMaterialStatus":"documentado","physicalMaterialSource":"Secciones del fabricante: capa de limpieza de 100 mm; nota 2CED5","appearanceStatus":"criterio_visual","appearanceBasis":"Interpretación visual del material documental; el acabado, tono y parámetros PBR no son una especificación contractual.","note":"La apariencia gráfica no modifica ni confirma la especificación física del material."} | {"elementId":"found_0904_f7e6bebab60859","ifcGuid":"1KvxXG15jNhuCwgv4PaY$U","ifcClass":"IfcSlab","buildingId":"process_plant","buildingName":"Zona de separación de aire","sourceDocumentId":"LHD2609-JG00100-20260904","sourceRepresentationKind":"foundation"} | {"profileId":"concrete_ha20","name":"Hormigón de limpieza HA-20","status":"criterio_visual","basis":"Interpretación visual del material documental; el acabado, tono y parámetros PBR no son una especificación contractual.","physicalMaterialUnchanged":true} | CB-MAIN, CB-HX-PLAN, CB-EXP-N-PLAN, CB-EXP-W-PLAN | 240F/2420, 240F/250C, 240F/250D, 240F/250E, 240F/250F, 240F/2510, 1FCF3 | Hormigón de limpieza HA-20 | -1.6 | -1.5 | 144.355 | 14.4355 | Sección y contornos del fabricante; incidencias conservadas | Hormigón de limpieza HA-20 | found_0904_f7e6bebab60859 | documentado | Secciones del fabricante: capa de limpieza de 100 mm; nota 2CED5 | 11.49 | 14.88 | concrete_ha20 | [0.721569,0.709804,0.658824] | 0.98 | Sección 4–4: etiqueta inferior −1,000 m frente a 1500 mm. Sección 4a–4a y espesor1500 mm: −1,500 m. Se adopta −1,500 m; conflicto pendiente. | JH_InformacionBIM - conceptualReferenceIds: ["CB-HX-CONCEPT","CB-EXP-N-CONCEPT","CB-EXP-W-CONCEPT"]; JH_ReferenciasDeEsquema - ObjetosIlustrativos: ["CB-HX-CONCEPT","CB-EXP-N-CONCEPT","CB-EXP-W-CONCEPT"]; Nota: Relación de visualización, no conexión de montaje aprobada.
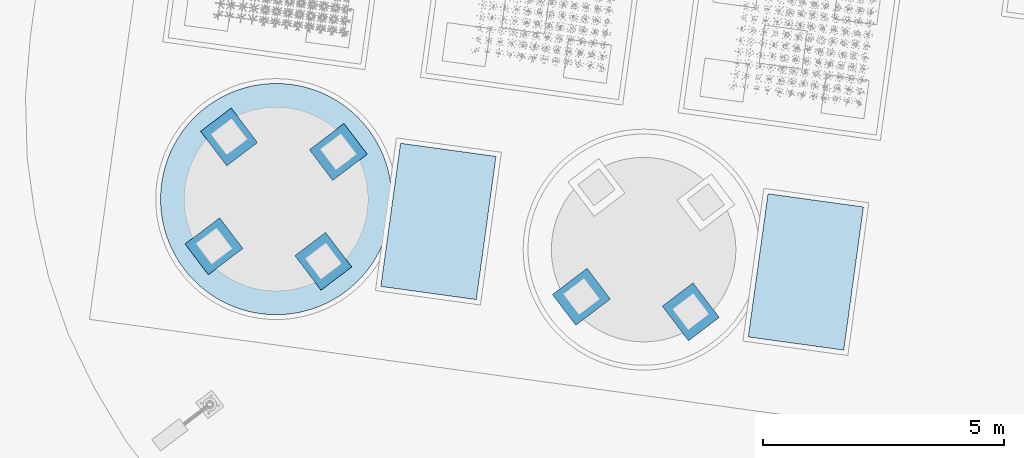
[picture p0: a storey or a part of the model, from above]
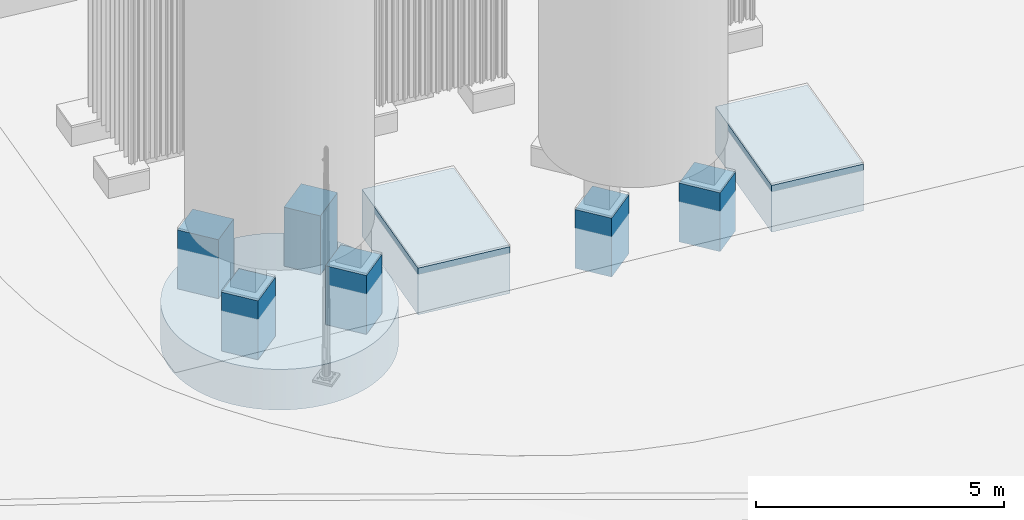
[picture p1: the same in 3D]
Properties of the parts of a building model (IFC4), part 103 of 134

# IfcSlab: Cimentación industrial (108)
Name | Material | Extensión de la malla en X (m) = ExtensionX (m) | Extensión de la malla en Y (m) = ExtensionY (m) | Extensión de la malla en Z (m) = ExtensionZ (m) = Espesor o altura real de sección (m) | Cota inferior de visualización (m) | Cota superior de visualización (m) | SuperficieDeLaMalla (m2) | VolumenGeometrico (m3) | JH_InformacionBIM, source = DocumentoFuente | material | dimensions | issues = IncidenciasPendientes | positioning = PosicionYEstado | assemblyId = Conjunto de cimentación | equipmentIds | supportPositionIds | sectionRef = Sección de referencia | sourceCadHandles | stableElementKey | geometryMetrics | materialAppearance | visualizationIdentity | appearance | Equipos asociados | Identificadores CAD de referencia | JH_Trazabilidad, Material = name | Cota inferior relativa (m) = Cota inferior relativa adoptada (m) | Cota superior relativa (m) = Cota superior relativa adoptada (m) | Área de planta (m²) | Volumen geométrico (m³) | Estado de la geometría | Acabado de visualización = Acabado | Identificador | status | JH_EvidenciaDeMaterial, source | Extensión local X (m) | Extensión local Y (m) | Perfil | ColorRGB | Rugosidad | Incidencias de origen
Cimentación del evaporador de residuos · apoyo rectangular · capa de limpieza | Hormigón de limpieza HA-20 | 1.98073 | 1.29287 | 0.1 | 285 | 285.1 | 4.4765 | 0.194775 | {"documentId":"LHD2609-JG00100-20260904","title":"Cimentaciones de equipos y pedestales del fabricante · revisión recibida 04/09/2026","date":"2026-09-04","sheet":"5–5","fileName":"LHD2609-JG00100_20260904.dwg","revisionCaveat":"Fecha de revisión tomada del nombre recibido; cajetines internos mantienen 02/07/2026 y algunos textos de plantilla.","sourceFileSha256":"b42eb027b7bc0b14c38d1d13514f4899b58a732aa8d0ba2ccf10fa2fc3192890"} | {"name":"Hormigón de limpieza HA-20","status":"documentado","source":"Secciones del fabricante: capa de limpieza de 100 mm; nota 2CED5"} | {"documented":[{"label":"Extensión local X","value":1.855,"unit":"m","source":"2516/2530, 2516/2520, 28CA5","status":"derivada del contorno CAD"},{"label":"Extensión local Y","value":1.05,"unit":"m","source":"2516/2530, 2516/2520, 28CA5","status":"derivada del contorno CAD"},{"label":"Cota inferior relativa adoptada","value":-1.1,"unit":"m","source":"5–5","status":"interpretación con conflicto conservado"},{"label":"Cota superior relativa adoptada","value":-1,"unit":"m","source":"5–5","status":"documentada / separación por material"}],"geometry":[{"label":"Extensión de la malla en X","value":1.9807270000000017,"unit":"m","source":"Geometría releída del IFC; datum absoluto de proceso provisional","status":"derivado"},{"label":"Extensión de la malla en Y","value":1.2928730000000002,"unit":"m","source":"Geometría releída del IFC; datum absoluto de proceso provisional","status":"derivado"},{"label":"Extensión de la malla en Z","value":0.1,"unit":"m","source":"Geometría releída del IFC; datum absoluto de proceso provisional","status":"derivado"},{"label":"Cota inferior de visualización","value":285.0,"unit":"m","source":"Geometría releída del IFC; datum absoluto de proceso provisional","status":"derivado"},{"label":"Cota superior de visualización","value":285.1,"unit":"m","source":"Geometría releída del IFC; datum absoluto de proceso provisional","status":"derivado"}]} | ["La longitud de la base rectangular varía entre la planta y la cadena de cotas de sección. Se conserva el contorno CAD general de 1,655 × 0,850 m."] | {"Cota inferior relativa (m)":-1.1,"Cota superior relativa (m)":-1,"Cero absoluto de visualización (m)":286.1,"Estado del cero absoluto":"Provisional","Criterio":"Las cotas relativas proceden del dibujo; la equivalencia absoluta no está confirmada."} | F-RESIDUAL | [] | [] | 5–5 | ["2516/2530","2516/2520","28CA5"] | F-RESIDUAL/Cimentación del evaporador de residuos · apoyo rectangular · capa de limpieza | {"boundingBoxM":{"min":[48.275596,38.675634,0.0],"max":[50.256323,39.968507,0.1]},"extentsM":[1.980727,1.292873,0.1],"meshSurfaceM2":4.476501,"meshVolumeM3":0.194775,"closedSolid":true,"basis":"Magnitudes de las mallas representadas, no cantidades certificadas de obra, compra o fabricación. Las partes pueden compartir superficies; no se suman como un despiece de materiales."} | {"profileId":"concrete_ha20","name":"Hormigón de limpieza HA-20","materialName":"Hormigón de limpieza HA-20","physicalMaterialStatus":"documentado","physicalMaterialSource":"Secciones del fabricante: capa de limpieza de 100 mm; nota 2CED5","appearanceStatus":"criterio_visual","appearanceBasis":"Interpretación visual del material documental; el acabado, tono y parámetros PBR no son una especificación contractual.","note":"La apariencia gráfica no modifica ni confirma la especificación física del material."} | {"elementId":"found_0904_c8fb0ee27d05a2","ifcGuid":"24uB4XQTPL2w$3spc9sMtN","ifcClass":"IfcSlab","buildingId":"process_plant","buildingName":"Zona de separación de aire","sourceDocumentId":"LHD2609-JG00100-20260904","sourceRepresentationKind":"foundation"} | {"profileId":"concrete_ha20","name":"Hormigón de limpieza HA-20","status":"criterio_visual","basis":"Interpretación visual del material documental; el acabado, tono y parámetros PBR no son una especificación contractual.","physicalMaterialUnchanged":true} |  | 2516/2530, 2516/2520, 28CA5 | Hormigón de limpieza HA-20 | -1.1 | -1 | 1.94775 | 0.194775 | Sección y contornos del fabricante; incidencias conservadas | Hormigón de limpieza HA-20 | found_0904_c8fb0ee27d05a2 | documentado | Secciones del fabricante: capa de limpieza de 100 mm; nota 2CED5 | 1.855 | 1.05 | concrete_ha20 | [0.721569,0.709804,0.658824] | 0.98 | La longitud de la base rectangular varía entre la planta y la cadena de cotas de sección. Se conserva el contorno CAD general de 1,655 × 0,850 m.
Cimentación del evaporador de residuos · apoyo rectangular · mortero superior de 50 mm | Mortero HA-35 de alta resistencia sin retracción | 1.75535 | 1.0675 | 0.05 | 286.77 | 286.82 | 3.064 | 0.070337 | {"documentId":"LHD2609-JG00100-20260904","title":"Cimentaciones de equipos y pedestales del fabricante · revisión recibida 04/09/2026","date":"2026-09-04","sheet":"5–5","fileName":"LHD2609-JG00100_20260904.dwg","revisionCaveat":"Fecha de revisión tomada del nombre recibido; cajetines internos mantienen 02/07/2026 y algunos textos de plantilla.","sourceFileSha256":"b42eb027b7bc0b14c38d1d13514f4899b58a732aa8d0ba2ccf10fa2fc3192890"} | {"name":"Mortero HA-35 de alta resistencia sin retracción","status":"documentado","source":"Capa superior de 50 mm expresada en las secciones del fabricante"} | {"documented":[{"label":"Extensión local X","value":1.655,"unit":"m","source":"2516/2530, 2516/2520, 28CA5","status":"derivada del contorno CAD"},{"label":"Extensión local Y","value":0.85,"unit":"m","source":"2516/2530, 2516/2520, 28CA5","status":"derivada del contorno CAD"},{"label":"Cota inferior relativa adoptada","value":0.6699999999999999,"unit":"m","source":"5–5","status":"interpretación con conflicto conservado"},{"label":"Cota superior relativa adoptada","value":0.72,"unit":"m","source":"5–5","status":"documentada / separación por material"}],"geometry":[{"label":"Extensión de la malla en X","value":1.75535,"unit":"m","source":"Geometría releída del IFC; datum absoluto de proceso provisional","status":"derivado"},{"label":"Extensión de la malla en Y","value":1.0674959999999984,"unit":"m","source":"Geometría releída del IFC; datum absoluto de proceso provisional","status":"derivado"},{"label":"Extensión de la malla en Z","value":0.050000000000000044,"unit":"m","source":"Geometría releída del IFC; datum absoluto de proceso provisional","status":"derivado"},{"label":"Cota inferior de visualización","value":286.77,"unit":"m","source":"Geometría releída del IFC; datum absoluto de proceso provisional","status":"derivado"},{"label":"Cota superior de visualización","value":286.82,"unit":"m","source":"Geometría releída del IFC; datum absoluto de proceso provisional","status":"derivado"}]} | ["La longitud de la base rectangular varía entre la planta y la cadena de cotas de sección. Se conserva el contorno CAD general de 1,655 × 0,850 m."] | {"Cota inferior relativa (m)":0.6699999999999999,"Cota superior relativa (m)":0.72,"Cero absoluto de visualización (m)":286.1,"Estado del cero absoluto":"Provisional","Criterio":"Las cotas relativas proceden del dibujo; la equivalencia absoluta no está confirmada."} | F-RESIDUAL | [] | [] | 5–5 | ["2516/2530","2516/2520","28CA5"] | F-RESIDUAL/Cimentación del evaporador de residuos · apoyo rectangular · mortero superior de 50 mm | {"boundingBoxM":{"min":[48.388285,38.788323,1.77],"max":[50.143635,39.855819,1.82]},"extentsM":[1.75535,1.067496,0.05],"meshSurfaceM2":3.064,"meshVolumeM3":0.070337,"closedSolid":true,"basis":"Magnitudes de las mallas representadas, no cantidades certificadas de obra, compra o fabricación. Las partes pueden compartir superficies; no se suman como un despiece de materiales."} | {"profileId":"grout_ha35","name":"Grout HA-35 sin retracción","materialName":"Mortero HA-35 de alta resistencia sin retracción","physicalMaterialStatus":"documentado","physicalMaterialSource":"Capa superior de 50 mm expresada en las secciones del fabricante","appearanceStatus":"criterio_visual","appearanceBasis":"Interpretación visual del material documental; el acabado, tono y parámetros PBR no son una especificación contractual.","note":"La apariencia gráfica no modifica ni confirma la especificación física del material."} | {"elementId":"found_0904_8fa5c2e1553f10","ifcGuid":"1NQbDx2FHN4A04koGJWaY3","ifcClass":"IfcSlab","buildingId":"process_plant","buildingName":"Zona de separación de aire","sourceDocumentId":"LHD2609-JG00100-20260904","sourceRepresentationKind":"foundation"} | {"profileId":"grout_ha35","name":"Grout HA-35 sin retracción","status":"criterio_visual","basis":"Interpretación visual del material documental; el acabado, tono y parámetros PBR no son una especificación contractual.","physicalMaterialUnchanged":true} |  | 2516/2530, 2516/2520, 28CA5 | Mortero HA-35 de alta resistencia sin retracción | 0.67 | 0.72 | 1.40675 | 0.070338 | Sección y contornos del fabricante; incidencias conservadas | Grout HA-35 sin retracción | found_0904_8fa5c2e1553f10 | documentado | Capa superior de 50 mm expresada en las secciones del fabricante | 1.655 | 0.85 | grout_ha35 | [0.792157,0.776471,0.721569] | 0.94 | La longitud de la base rectangular varía entre la planta y la cadena de cotas de sección. Se conserva el contorno CAD general de 1,655 × 0,850 m.
Cimentación del evaporador de residuos · apoyo circular · capa de limpieza | Hormigón de limpieza HA-20 | 1.3 | 1.30001 | 0.1 | 285 | 285.1 | 3.06268 | 0.132714 | {"documentId":"LHD2609-JG00100-20260904","title":"Cimentaciones de equipos y pedestales del fabricante · revisión recibida 04/09/2026","date":"2026-09-04","sheet":"5–5","fileName":"LHD2609-JG00100_20260904.dwg","revisionCaveat":"Fecha de revisión tomada del nombre recibido; cajetines internos mantienen 02/07/2026 y algunos textos de plantilla.","sourceFileSha256":"b42eb027b7bc0b14c38d1d13514f4899b58a732aa8d0ba2ccf10fa2fc3192890"} | {"name":"Hormigón de limpieza HA-20","status":"documentado","source":"Secciones del fabricante: capa de limpieza de 100 mm; nota 2CED5"} | {"documented":[{"label":"Extensión local X","value":1.300027,"unit":"m","source":"2516/2530, 2516/2520, 28CA5","status":"derivada del contorno CAD"},{"label":"Extensión local Y","value":1.300027,"unit":"m","source":"2516/2530, 2516/2520, 28CA5","status":"derivada del contorno CAD"},{"label":"Cota inferior relativa adoptada","value":-1.1,"unit":"m","source":"5–5","status":"interpretación con conflicto conservado"},{"label":"Cota superior relativa adoptada","value":-1,"unit":"m","source":"5–5","status":"documentada / separación por material"}],"geometry":[{"label":"Extensión de la malla en X","value":1.3000049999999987,"unit":"m","source":"Geometría releída del IFC; datum absoluto de proceso provisional","status":"derivado"},{"label":"Extensión de la malla en Y","value":1.3000060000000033,"unit":"m","source":"Geometría releída del IFC; datum absoluto de proceso provisional","status":"derivado"},{"label":"Extensión de la malla en Z","value":0.1,"unit":"m","source":"Geometría releída del IFC; datum absoluto de proceso provisional","status":"derivado"},{"label":"Cota inferior de visualización","value":285.0,"unit":"m","source":"Geometría releída del IFC; datum absoluto de proceso provisional","status":"derivado"},{"label":"Cota superior de visualización","value":285.1,"unit":"m","source":"Geometría releída del IFC; datum absoluto de proceso provisional","status":"derivado"}]} | ["La longitud de la base rectangular varía entre la planta y la cadena de cotas de sección. Se conserva el contorno CAD general de 1,655 × 0,850 m."] | {"Cota inferior relativa (m)":-1.1,"Cota superior relativa (m)":-1,"Cero absoluto de visualización (m)":286.1,"Estado del cero absoluto":"Provisional","Criterio":"Las cotas relativas proceden del dibujo; la equivalencia absoluta no está confirmada."} | F-RESIDUAL | [] | [] | 5–5 | ["2516/2530","2516/2520","28CA5"] | F-RESIDUAL/Cimentación del evaporador de residuos · apoyo circular · capa de limpieza | {"boundingBoxM":{"min":[50.259001,38.446174,0.0],"max":[51.559006,39.74618,0.1]},"extentsM":[1.300005,1.300006,0.1],"meshSurfaceM2":3.062679,"meshVolumeM3":0.132714,"closedSolid":true,"basis":"Magnitudes de las mallas representadas, no cantidades certificadas de obra, compra o fabricación. Las partes pueden compartir superficies; no se suman como un despiece de materiales."} | {"profileId":"concrete_ha20","name":"Hormigón de limpieza HA-20","materialName":"Hormigón de limpieza HA-20","physicalMaterialStatus":"documentado","physicalMaterialSource":"Secciones del fabricante: capa de limpieza de 100 mm; nota 2CED5","appearanceStatus":"criterio_visual","appearanceBasis":"Interpretación visual del material documental; el acabado, tono y parámetros PBR no son una especificación contractual.","note":"La apariencia gráfica no modifica ni confirma la especificación física del material."} | {"elementId":"found_0904_e556d96428fbeb","ifcGuid":"2s$1AU4WXGbAUl0qkHCIw7","ifcClass":"IfcSlab","buildingId":"process_plant","buildingName":"Zona de separación de aire","sourceDocumentId":"LHD2609-JG00100-20260904","sourceRepresentationKind":"foundation"} | {"profileId":"concrete_ha20","name":"Hormigón de limpieza HA-20","status":"criterio_visual","basis":"Interpretación visual del material documental; el acabado, tono y parámetros PBR no son una especificación contractual.","physicalMaterialUnchanged":true} |  | 2516/2530, 2516/2520, 28CA5 | Hormigón de limpieza HA-20 | -1.1 | -1 | 1.32714 | 0.132714 | Sección y contornos del fabricante; incidencias conservadas | Hormigón de limpieza HA-20 | found_0904_e556d96428fbeb | documentado | Secciones del fabricante: capa de limpieza de 100 mm; nota 2CED5 | 1.30003 | 1.30003 | concrete_ha20 | [0.721569,0.709804,0.658824] | 0.98 | La longitud de la base rectangular varía entre la planta y la cadena de cotas de sección. Se conserva el contorno CAD general de 1,655 × 0,850 m.
Cimentación del evaporador de residuos · apoyo circular · mortero superior de 50 mm | Mortero HA-35 de alta resistencia sin retracción | 1.09998 | 1.09998 | 0.05 | 286.25 | 286.3 | 2.0731 | 0.047508 | {"documentId":"LHD2609-JG00100-20260904","title":"Cimentaciones de equipos y pedestales del fabricante · revisión recibida 04/09/2026","date":"2026-09-04","sheet":"5–5","fileName":"LHD2609-JG00100_20260904.dwg","revisionCaveat":"Fecha de revisión tomada del nombre recibido; cajetines internos mantienen 02/07/2026 y algunos textos de plantilla.","sourceFileSha256":"b42eb027b7bc0b14c38d1d13514f4899b58a732aa8d0ba2ccf10fa2fc3192890"} | {"name":"Mortero HA-35 de alta resistencia sin retracción","status":"documentado","source":"Capa superior de 50 mm expresada en las secciones del fabricante"} | {"documented":[{"label":"Extensión local X","value":1.1,"unit":"m","source":"2516/2530, 2516/2520, 28CA5","status":"derivada del contorno CAD"},{"label":"Extensión local Y","value":1.1,"unit":"m","source":"2516/2530, 2516/2520, 28CA5","status":"derivada del contorno CAD"},{"label":"Cota inferior relativa adoptada","value":0.15000000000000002,"unit":"m","source":"5–5","status":"interpretación con conflicto conservado"},{"label":"Cota superior relativa adoptada","value":0.2,"unit":"m","source":"5–5","status":"documentada / separación por material"}],"geometry":[{"label":"Extensión de la malla en X","value":1.0999809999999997,"unit":"m","source":"Geometría releída del IFC; datum absoluto de proceso provisional","status":"derivado"},{"label":"Extensión de la malla en Y","value":1.0999820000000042,"unit":"m","source":"Geometría releída del IFC; datum absoluto de proceso provisional","status":"derivado"},{"label":"Extensión de la malla en Z","value":0.050000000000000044,"unit":"m","source":"Geometría releída del IFC; datum absoluto de proceso provisional","status":"derivado"},{"label":"Cota inferior de visualización","value":286.25,"unit":"m","source":"Geometría releída del IFC; datum absoluto de proceso provisional","status":"derivado"},{"label":"Cota superior de visualización","value":286.3,"unit":"m","source":"Geometría releída del IFC; datum absoluto de proceso provisional","status":"derivado"}]} | ["La longitud de la base rectangular varía entre la planta y la cadena de cotas de sección. Se conserva el contorno CAD general de 1,655 × 0,850 m."] | {"Cota inferior relativa (m)":0.15000000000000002,"Cota superior relativa (m)":0.2,"Cero absoluto de visualización (m)":286.1,"Estado del cero absoluto":"Provisional","Criterio":"Las cotas relativas proceden del dibujo; la equivalencia absoluta no está confirmada."} | F-RESIDUAL | [] | [] | 5–5 | ["2516/2530","2516/2520","28CA5"] | F-RESIDUAL/Cimentación del evaporador de residuos · apoyo circular · mortero superior de 50 mm | {"boundingBoxM":{"min":[50.359013,38.546186,1.25],"max":[51.458994,39.646168,1.3]},"extentsM":[1.099981,1.099982,0.05],"meshSurfaceM2":2.073104,"meshVolumeM3":0.047508,"closedSolid":true,"basis":"Magnitudes de las mallas representadas, no cantidades certificadas de obra, compra o fabricación. Las partes pueden compartir superficies; no se suman como un despiece de materiales."} | {"profileId":"grout_ha35","name":"Grout HA-35 sin retracción","materialName":"Mortero HA-35 de alta resistencia sin retracción","physicalMaterialStatus":"documentado","physicalMaterialSource":"Capa superior de 50 mm expresada en las secciones del fabricante","appearanceStatus":"criterio_visual","appearanceBasis":"Interpretación visual del material documental; el acabado, tono y parámetros PBR no son una especificación contractual.","note":"La apariencia gráfica no modifica ni confirma la especificación física del material."} | {"elementId":"found_0904_865f1f3a88948f","ifcGuid":"0PTFq2gazIqv6fML$TZeaq","ifcClass":"IfcSlab","buildingId":"process_plant","buildingName":"Zona de separación de aire","sourceDocumentId":"LHD2609-JG00100-20260904","sourceRepresentationKind":"foundation"} | {"profileId":"grout_ha35","name":"Grout HA-35 sin retracción","status":"criterio_visual","basis":"Interpretación visual del material documental; el acabado, tono y parámetros PBR no son una especificación contractual.","physicalMaterialUnchanged":true} |  | 2516/2530, 2516/2520, 28CA5 | Mortero HA-35 de alta resistencia sin retracción | 0.15 | 0.2 | 0.950162 | 0.047508 | Sección y contornos del fabricante; incidencias conservadas | Grout HA-35 sin retracción | found_0904_865f1f3a88948f | documentado | Capa superior de 50 mm expresada en las secciones del fabricante | 1.1 | 1.1 | grout_ha35 | [0.792157,0.776471,0.721569] | 0.94 | La longitud de la base rectangular varía entre la planta y la cadena de cotas de sección. Se conserva el contorno CAD general de 1,655 × 0,850 m.
Cimentación del posenfriador WE441-PLAN · capa de limpieza | Hormigón de limpieza HA-20 | 1.54295 | 2.73922 | 0.1 | 284 | 284.1 | 7 | 0.312 | {"documentId":"LHD2609-JG00100-20260904","title":"Cimentaciones de equipos y pedestales del fabricante · revisión recibida 04/09/2026","date":"2026-09-04","sheet":"6–6","fileName":"LHD2609-JG00100_20260904.dwg","revisionCaveat":"Fecha de revisión tomada del nombre recibido; cajetines internos mantienen 02/07/2026 y algunos textos de plantilla.","sourceFileSha256":"b42eb027b7bc0b14c38d1d13514f4899b58a732aa8d0ba2ccf10fa2fc3192890"} | {"name":"Hormigón de limpieza HA-20","status":"documentado","source":"Secciones del fabricante: capa de limpieza de 100 mm; nota 2CED5"} | {"documented":[{"label":"Extensión local X","value":1.2,"unit":"m","source":"433C/27BC, 433C/27BD, 433C/E6A3, 28D71","status":"derivada del contorno CAD"},{"label":"Extensión local Y","value":2.6,"unit":"m","source":"433C/27BC, 433C/27BD, 433C/E6A3, 28D71","status":"derivada del contorno CAD"},{"label":"Cota inferior relativa adoptada","value":-2.1,"unit":"m","source":"6–6","status":"interpretación con conflicto conservado"},{"label":"Cota superior relativa adoptada","value":-2,"unit":"m","source":"6–6","status":"documentada / separación por material"}],"geometry":[{"label":"Extensión de la malla en X","value":1.542946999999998,"unit":"m","source":"Geometría releída del IFC; datum absoluto de proceso provisional","status":"derivado"},{"label":"Extensión de la malla en Y","value":2.7392150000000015,"unit":"m","source":"Geometría releída del IFC; datum absoluto de proceso provisional","status":"derivado"},{"label":"Extensión de la malla en Z","value":0.09999999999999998,"unit":"m","source":"Geometría releída del IFC; datum absoluto de proceso provisional","status":"derivado"},{"label":"Cota inferior de visualización","value":284.0,"unit":"m","source":"Geometría releída del IFC; datum absoluto de proceso provisional","status":"derivado"},{"label":"Cota superior de visualización","value":284.1,"unit":"m","source":"Geometría releída del IFC; datum absoluto de proceso provisional","status":"derivado"}]} | ["Planta: −2,200 m. Sección 6–6: fondo −2,000 m y coronación de losa −1,200 m. Se adopta sección; pendiente de aclaración."] | {"Cota inferior relativa (m)":-2.1,"Cota superior relativa (m)":-2,"Cero absoluto de visualización (m)":286.1,"Estado del cero absoluto":"Provisional","Criterio":"Las cotas relativas proceden del dibujo; la equivalencia absoluta no está confirmada."} | F-WE441-PLAN | ["WE441-PLAN"] | [] | 6–6 | ["433C/27BC","433C/27BD","433C/E6A3","28D71"] | F-WE441-PLAN/Cimentación del posenfriador WE441-PLAN · capa de limpieza | {"boundingBoxM":{"min":[46.157285,46.954829,-1.0],"max":[47.700232,49.694044,-0.9]},"extentsM":[1.542947,2.739215,0.1],"meshSurfaceM2":7.0,"meshVolumeM3":0.312,"closedSolid":true,"basis":"Magnitudes de las mallas representadas, no cantidades certificadas de obra, compra o fabricación. Las partes pueden compartir superficies; no se suman como un despiece de materiales."} | {"profileId":"concrete_ha20","name":"Hormigón de limpieza HA-20","materialName":"Hormigón de limpieza HA-20","physicalMaterialStatus":"documentado","physicalMaterialSource":"Secciones del fabricante: capa de limpieza de 100 mm; nota 2CED5","appearanceStatus":"criterio_visual","appearanceBasis":"Interpretación visual del material documental; el acabado, tono y parámetros PBR no son una especificación contractual.","note":"La apariencia gráfica no modifica ni confirma la especificación física del material."} | {"elementId":"found_0904_8f5d425169405d","ifcGuid":"2Y0Ww_jivSDxL6AkRYLvAn","ifcClass":"IfcSlab","buildingId":"process_plant","buildingName":"Zona de separación de aire","sourceDocumentId":"LHD2609-JG00100-20260904","sourceRepresentationKind":"foundation"} | {"profileId":"concrete_ha20","name":"Hormigón de limpieza HA-20","status":"criterio_visual","basis":"Interpretación visual del material documental; el acabado, tono y parámetros PBR no son una especificación contractual.","physicalMaterialUnchanged":true} | WE441-PLAN | 433C/27BC, 433C/27BD, 433C/E6A3, 28D71 | Hormigón de limpieza HA-20 | -2.1 | -2 | 3.12 | 0.312 | Sección y contornos del fabricante; incidencias conservadas | Hormigón de limpieza HA-20 | found_0904_8f5d425169405d | documentado | Secciones del fabricante: capa de limpieza de 100 mm; nota 2CED5 | 1.2 | 2.6 | concrete_ha20 | [0.721569,0.709804,0.658824] | 0.98 | Planta: −2,200 m. Sección 6–6: fondo −2,000 m y coronación de losa −1,200 m. Se adopta sección; pendiente de aclaración.
Cimentación del posenfriador WE441-PLAN · mortero DZ6 1 | Mortero HA-35 de alta resistencia sin retracción | 0.635269 | 0.378926 | 0.05 | 286.25 | 286.3 | 0.449999 | 0.009 | {"documentId":"LHD2609-JG00100-20260904","title":"Cimentaciones de equipos y pedestales del fabricante · revisión recibida 04/09/2026","date":"2026-09-04","sheet":"6–6","fileName":"LHD2609-JG00100_20260904.dwg","revisionCaveat":"Fecha de revisión tomada del nombre recibido; cajetines internos mantienen 02/07/2026 y algunos textos de plantilla.","sourceFileSha256":"b42eb027b7bc0b14c38d1d13514f4899b58a732aa8d0ba2ccf10fa2fc3192890"} | {"name":"Mortero HA-35 de alta resistencia sin retracción","status":"documentado","source":"Capa superior de 50 mm expresada en las secciones del fabricante"} | {"documented":[{"label":"Extensión local X","value":0.6,"unit":"m","source":"433C/27BC, 433C/27BD, 433C/E6A3, 28D71","status":"derivada del contorno CAD"},{"label":"Extensión local Y","value":0.3,"unit":"m","source":"433C/27BC, 433C/27BD, 433C/E6A3, 28D71","status":"derivada del contorno CAD"},{"label":"Cota inferior relativa adoptada","value":0.15,"unit":"m","source":"6–6","status":"interpretación con conflicto conservado"},{"label":"Cota superior relativa adoptada","value":0.2,"unit":"m","source":"6–6","status":"documentada / separación por material"}],"geometry":[{"label":"Extensión de la malla en X","value":0.635269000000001,"unit":"m","source":"Geometría releída del IFC; datum absoluto de proceso provisional","status":"derivado"},{"label":"Extensión de la malla en Y","value":0.3789259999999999,"unit":"m","source":"Geometría releída del IFC; datum absoluto de proceso provisional","status":"derivado"},{"label":"Extensión de la malla en Z","value":0.050000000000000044,"unit":"m","source":"Geometría releída del IFC; datum absoluto de proceso provisional","status":"derivado"},{"label":"Cota inferior de visualización","value":286.25,"unit":"m","source":"Geometría releída del IFC; datum absoluto de proceso provisional","status":"derivado"},{"label":"Cota superior de visualización","value":286.3,"unit":"m","source":"Geometría releída del IFC; datum absoluto de proceso provisional","status":"derivado"}]} | ["Planta: −2,200 m. Sección 6–6: fondo −2,000 m y coronación de losa −1,200 m. Se adopta sección; pendiente de aclaración."] | {"Cota inferior relativa (m)":0.15,"Cota superior relativa (m)":0.2,"Cero absoluto de visualización (m)":286.1,"Estado del cero absoluto":"Provisional","Criterio":"Las cotas relativas proceden del dibujo; la equivalencia absoluta no está confirmada."} | F-WE441-PLAN | ["WE441-PLAN"] | [] | 6–6 | ["433C/27BC","433C/27BD","433C/E6A3","28D71"] | F-WE441-PLAN/Cimentación del posenfriador WE441-PLAN · mortero DZ6 1 | {"boundingBoxM":{"min":[46.713277,48.877984,1.25],"max":[47.348546,49.25691,1.3]},"extentsM":[0.635269,0.378926,0.05],"meshSurfaceM2":0.449999,"meshVolumeM3":0.009,"closedSolid":true,"basis":"Magnitudes de las mallas representadas, no cantidades certificadas de obra, compra o fabricación. Las partes pueden compartir superficies; no se suman como un despiece de materiales."} | {"profileId":"grout_ha35","name":"Grout HA-35 sin retracción","materialName":"Mortero HA-35 de alta resistencia sin retracción","physicalMaterialStatus":"documentado","physicalMaterialSource":"Capa superior de 50 mm expresada en las secciones del fabricante","appearanceStatus":"criterio_visual","appearanceBasis":"Interpretación visual del material documental; el acabado, tono y parámetros PBR no son una especificación contractual.","note":"La apariencia gráfica no modifica ni confirma la especificación física del material."} | {"elementId":"found_0904_6ce123701091e4","ifcGuid":"1qtcLLYnnMYgWrdSETJQw5","ifcClass":"IfcSlab","buildingId":"process_plant","buildingName":"Zona de separación de aire","sourceDocumentId":"LHD2609-JG00100-20260904","sourceRepresentationKind":"foundation"} | {"profileId":"grout_ha35","name":"Grout HA-35 sin retracción","status":"criterio_visual","basis":"Interpretación visual del material documental; el acabado, tono y parámetros PBR no son una especificación contractual.","physicalMaterialUnchanged":true} | WE441-PLAN | 433C/27BC, 433C/27BD, 433C/E6A3, 28D71 | Mortero HA-35 de alta resistencia sin retracción | 0.15 | 0.2 | 0.18 | 0.009 | Sección y contornos del fabricante; incidencias conservadas | Grout HA-35 sin retracción | found_0904_6ce123701091e4 | documentado | Capa superior de 50 mm expresada en las secciones del fabricante | 0.6 | 0.3 | grout_ha35 | [0.792157,0.776471,0.721569] | 0.94 | Planta: −2,200 m. Sección 6–6: fondo −2,000 m y coronación de losa −1,200 m. Se adopta sección; pendiente de aclaración.
Cimentación del posenfriador WE441-PLAN · mortero DZ6 2 | Mortero HA-35 de alta resistencia sin retracción | 0.635269 | 0.378927 | 0.05 | 286.25 | 286.3 | 0.45 | 0.009 | {"documentId":"LHD2609-JG00100-20260904","title":"Cimentaciones de equipos y pedestales del fabricante · revisión recibida 04/09/2026","date":"2026-09-04","sheet":"6–6","fileName":"LHD2609-JG00100_20260904.dwg","revisionCaveat":"Fecha de revisión tomada del nombre recibido; cajetines internos mantienen 02/07/2026 y algunos textos de plantilla.","sourceFileSha256":"b42eb027b7bc0b14c38d1d13514f4899b58a732aa8d0ba2ccf10fa2fc3192890"} | {"name":"Mortero HA-35 de alta resistencia sin retracción","status":"documentado","source":"Capa superior de 50 mm expresada en las secciones del fabricante"} | {"documented":[{"label":"Extensión local X","value":0.6,"unit":"m","source":"433C/27BC, 433C/27BD, 433C/E6A3, 28D71","status":"derivada del contorno CAD"},{"label":"Extensión local Y","value":0.3,"unit":"m","source":"433C/27BC, 433C/27BD, 433C/E6A3, 28D71","status":"derivada del contorno CAD"},{"label":"Cota inferior relativa adoptada","value":0.15,"unit":"m","source":"6–6","status":"interpretación con conflicto conservado"},{"label":"Cota superior relativa adoptada","value":0.2,"unit":"m","source":"6–6","status":"documentada / separación por material"}],"geometry":[{"label":"Extensión de la malla en X","value":0.635269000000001,"unit":"m","source":"Geometría releída del IFC; datum absoluto de proceso provisional","status":"derivado"},{"label":"Extensión de la malla en Y","value":0.37892699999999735,"unit":"m","source":"Geometría releída del IFC; datum absoluto de proceso provisional","status":"derivado"},{"label":"Extensión de la malla en Z","value":0.050000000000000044,"unit":"m","source":"Geometría releída del IFC; datum absoluto de proceso provisional","status":"derivado"},{"label":"Cota inferior de visualización","value":286.25,"unit":"m","source":"Geometría releída del IFC; datum absoluto de proceso provisional","status":"derivado"},{"label":"Cota superior de visualización","value":286.3,"unit":"m","source":"Geometría releída del IFC; datum absoluto de proceso provisional","status":"derivado"}]} | ["Planta: −2,200 m. Sección 6–6: fondo −2,000 m y coronación de losa −1,200 m. Se adopta sección; pendiente de aclaración."] | {"Cota inferior relativa (m)":0.15,"Cota superior relativa (m)":0.2,"Cero absoluto de visualización (m)":286.1,"Estado del cero absoluto":"Provisional","Criterio":"Las cotas relativas proceden del dibujo; la equivalencia absoluta no está confirmada."} | F-WE441-PLAN | ["WE441-PLAN"] | [] | 6–6 | ["433C/27BC","433C/27BD","433C/E6A3","28D71"] | F-WE441-PLAN/Cimentación del posenfriador WE441-PLAN · mortero DZ6 2 | {"boundingBoxM":{"min":[46.508971,47.391962,1.25],"max":[47.14424,47.770889,1.3]},"extentsM":[0.635269,0.378927,0.05],"meshSurfaceM2":0.45,"meshVolumeM3":0.009,"closedSolid":true,"basis":"Magnitudes de las mallas representadas, no cantidades certificadas de obra, compra o fabricación. Las partes pueden compartir superficies; no se suman como un despiece de materiales."} | {"profileId":"grout_ha35","name":"Grout HA-35 sin retracción","materialName":"Mortero HA-35 de alta resistencia sin retracción","physicalMaterialStatus":"documentado","physicalMaterialSource":"Capa superior de 50 mm expresada en las secciones del fabricante","appearanceStatus":"criterio_visual","appearanceBasis":"Interpretación visual del material documental; el acabado, tono y parámetros PBR no son una especificación contractual.","note":"La apariencia gráfica no modifica ni confirma la especificación física del material."} | {"elementId":"found_0904_e1d719443855d4","ifcGuid":"0jTkB28IbOX9ayBCyJ$KZM","ifcClass":"IfcSlab","buildingId":"process_plant","buildingName":"Zona de separación de aire","sourceDocumentId":"LHD2609-JG00100-20260904","sourceRepresentationKind":"foundation"} | {"profileId":"grout_ha35","name":"Grout HA-35 sin retracción","status":"criterio_visual","basis":"Interpretación visual del material documental; el acabado, tono y parámetros PBR no son una especificación contractual.","physicalMaterialUnchanged":true} | WE441-PLAN | 433C/27BC, 433C/27BD, 433C/E6A3, 28D71 | Mortero HA-35 de alta resistencia sin retracción | 0.15 | 0.2 | 0.18 | 0.009 | Sección y contornos del fabricante; incidencias conservadas | Grout HA-35 sin retracción | found_0904_e1d719443855d4 | documentado | Capa superior de 50 mm expresada en las secciones del fabricante | 0.6 | 0.3 | grout_ha35 | [0.792157,0.776471,0.721569] | 0.94 | Planta: −2,200 m. Sección 6–6: fondo −2,000 m y coronación de losa −1,200 m. Se adopta sección; pendiente de aclaración.
Cimentación del posenfriador WE442-PLAN · capa de limpieza | Hormigón de limpieza HA-20 | 1.54295 | 2.73922 | 0.1 | 284 | 284.1 | 7 | 0.312 | {"documentId":"LHD2609-JG00100-20260904","title":"Cimentaciones de equipos y pedestales del fabricante · revisión recibida 04/09/2026","date":"2026-09-04","sheet":"6–6","fileName":"LHD2609-JG00100_20260904.dwg","revisionCaveat":"Fecha de revisión tomada del nombre recibido; cajetines internos mantienen 02/07/2026 y algunos textos de plantilla.","sourceFileSha256":"b42eb027b7bc0b14c38d1d13514f4899b58a732aa8d0ba2ccf10fa2fc3192890"} | {"name":"Hormigón de limpieza HA-20","status":"documentado","source":"Secciones del fabricante: capa de limpieza de 100 mm; nota 2CED5"} | {"documented":[{"label":"Extensión local X","value":1.2,"unit":"m","source":"27B6/27BC, 27B6/27BD, 27B6/E6A3, 28D71","status":"derivada del contorno CAD"},{"label":"Extensión local Y","value":2.6,"unit":"m","source":"27B6/27BC, 27B6/27BD, 27B6/E6A3, 28D71","status":"derivada del contorno CAD"},{"label":"Cota inferior relativa adoptada","value":-2.1,"unit":"m","source":"6–6","status":"interpretación con conflicto conservado"},{"label":"Cota superior relativa adoptada","value":-2,"unit":"m","source":"6–6","status":"documentada / separación por material"}],"geometry":[{"label":"Extensión de la malla en X","value":1.542946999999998,"unit":"m","source":"Geometría releída del IFC; datum absoluto de proceso provisional","status":"derivado"},{"label":"Extensión de la malla en Y","value":2.7392150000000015,"unit":"m","source":"Geometría releída del IFC; datum absoluto de proceso provisional","status":"derivado"},{"label":"Extensión de la malla en Z","value":0.09999999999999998,"unit":"m","source":"Geometría releída del IFC; datum absoluto de proceso provisional","status":"derivado"},{"label":"Cota inferior de visualización","value":284.0,"unit":"m","source":"Geometría releída del IFC; datum absoluto de proceso provisional","status":"derivado"},{"label":"Cota superior de visualización","value":284.1,"unit":"m","source":"Geometría releída del IFC; datum absoluto de proceso provisional","status":"derivado"}]} | ["Planta: −2,200 m. Sección 6–6: fondo −2,000 m y coronación de losa −1,200 m. Se adopta sección; pendiente de aclaración."] | {"Cota inferior relativa (m)":-2.1,"Cota superior relativa (m)":-2,"Cero absoluto de visualización (m)":286.1,"Estado del cero absoluto":"Provisional","Criterio":"Las cotas relativas proceden del dibujo; la equivalencia absoluta no está confirmada."} | F-WE442-PLAN | ["WE442-PLAN"] | [] | 6–6 | ["27B6/27BC","27B6/27BD","27B6/E6A3","28D71"] | F-WE442-PLAN/Cimentación del posenfriador WE442-PLAN · capa de limpieza | {"boundingBoxM":{"min":[47.544238,46.764143,-1.0],"max":[49.087185,49.503358,-0.9]},"extentsM":[1.542947,2.739215,0.1],"meshSurfaceM2":7.0,"meshVolumeM3":0.312,"closedSolid":true,"basis":"Magnitudes de las mallas representadas, no cantidades certificadas de obra, compra o fabricación. Las partes pueden compartir superficies; no se suman como un despiece de materiales."} | {"profileId":"concrete_ha20","name":"Hormigón de limpieza HA-20","materialName":"Hormigón de limpieza HA-20","physicalMaterialStatus":"documentado","physicalMaterialSource":"Secciones del fabricante: capa de limpieza de 100 mm; nota 2CED5","appearanceStatus":"criterio_visual","appearanceBasis":"Interpretación visual del material documental; el acabado, tono y parámetros PBR no son una especificación contractual.","note":"La apariencia gráfica no modifica ni confirma la especificación física del material."} | {"elementId":"found_0904_91ddea20df6ae4","ifcGuid":"1jHKF8KjfMI9VejqQT9x75","ifcClass":"IfcSlab","buildingId":"process_plant","buildingName":"Zona de separación de aire","sourceDocumentId":"LHD2609-JG00100-20260904","sourceRepresentationKind":"foundation"} | {"profileId":"concrete_ha20","name":"Hormigón de limpieza HA-20","status":"criterio_visual","basis":"Interpretación visual del material documental; el acabado, tono y parámetros PBR no son una especificación contractual.","physicalMaterialUnchanged":true} | WE442-PLAN | 27B6/27BC, 27B6/27BD, 27B6/E6A3, 28D71 | Hormigón de limpieza HA-20 | -2.1 | -2 | 3.12 | 0.312 | Sección y contornos del fabricante; incidencias conservadas | Hormigón de limpieza HA-20 | found_0904_91ddea20df6ae4 | documentado | Secciones del fabricante: capa de limpieza de 100 mm; nota 2CED5 | 1.2 | 2.6 | concrete_ha20 | [0.721569,0.709804,0.658824] | 0.98 | Planta: −2,200 m. Sección 6–6: fondo −2,000 m y coronación de losa −1,200 m. Se adopta sección; pendiente de aclaración.
Cimentación del posenfriador WE442-PLAN · mortero DZ6 1 | Mortero HA-35 de alta resistencia sin retracción | 0.63527 | 0.378927 | 0.05 | 286.25 | 286.3 | 0.45 | 0.009 | {"documentId":"LHD2609-JG00100-20260904","title":"Cimentaciones de equipos y pedestales del fabricante · revisión recibida 04/09/2026","date":"2026-09-04","sheet":"6–6","fileName":"LHD2609-JG00100_20260904.dwg","revisionCaveat":"Fecha de revisión tomada del nombre recibido; cajetines internos mantienen 02/07/2026 y algunos textos de plantilla.","sourceFileSha256":"b42eb027b7bc0b14c38d1d13514f4899b58a732aa8d0ba2ccf10fa2fc3192890"} | {"name":"Mortero HA-35 de alta resistencia sin retracción","status":"documentado","source":"Capa superior de 50 mm expresada en las secciones del fabricante"} | {"documented":[{"label":"Extensión local X","value":0.6,"unit":"m","source":"27B6/27BC, 27B6/27BD, 27B6/E6A3, 28D71","status":"derivada del contorno CAD"},{"label":"Extensión local Y","value":0.3,"unit":"m","source":"27B6/27BC, 27B6/27BD, 27B6/E6A3, 28D71","status":"derivada del contorno CAD"},{"label":"Cota inferior relativa adoptada","value":0.15,"unit":"m","source":"6–6","status":"interpretación con conflicto conservado"},{"label":"Cota superior relativa adoptada","value":0.2,"unit":"m","source":"6–6","status":"documentada / separación por material"}],"geometry":[{"label":"Extensión de la malla en X","value":0.6352699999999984,"unit":"m","source":"Geometría releída del IFC; datum absoluto de proceso provisional","status":"derivado"},{"label":"Extensión de la malla en Y","value":0.37892700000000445,"unit":"m","source":"Geometría releída del IFC; datum absoluto de proceso provisional","status":"derivado"},{"label":"Extensión de la malla en Z","value":0.050000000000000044,"unit":"m","source":"Geometría releída del IFC; datum absoluto de proceso provisional","status":"derivado"},{"label":"Cota inferior de visualización","value":286.25,"unit":"m","source":"Geometría releída del IFC; datum absoluto de proceso provisional","status":"derivado"},{"label":"Cota superior de visualización","value":286.3,"unit":"m","source":"Geometría releída del IFC; datum absoluto de proceso provisional","status":"derivado"}]} | ["Planta: −2,200 m. Sección 6–6: fondo −2,000 m y coronación de losa −1,200 m. Se adopta sección; pendiente de aclaración."] | {"Cota inferior relativa (m)":0.15,"Cota superior relativa (m)":0.2,"Cero absoluto de visualización (m)":286.1,"Estado del cero absoluto":"Provisional","Criterio":"Las cotas relativas proceden del dibujo; la equivalencia absoluta no está confirmada."} | F-WE442-PLAN | ["WE442-PLAN"] | [] | 6–6 | ["27B6/27BC","27B6/27BD","27B6/E6A3","28D71"] | F-WE442-PLAN/Cimentación del posenfriador WE442-PLAN · mortero DZ6 1 | {"boundingBoxM":{"min":[48.10023,48.687298,1.25],"max":[48.7355,49.066225,1.3]},"extentsM":[0.63527,0.378927,0.05],"meshSurfaceM2":0.45,"meshVolumeM3":0.009,"closedSolid":true,"basis":"Magnitudes de las mallas representadas, no cantidades certificadas de obra, compra o fabricación. Las partes pueden compartir superficies; no se suman como un despiece de materiales."} | {"profileId":"grout_ha35","name":"Grout HA-35 sin retracción","materialName":"Mortero HA-35 de alta resistencia sin retracción","physicalMaterialStatus":"documentado","physicalMaterialSource":"Capa superior de 50 mm expresada en las secciones del fabricante","appearanceStatus":"criterio_visual","appearanceBasis":"Interpretación visual del material documental; el acabado, tono y parámetros PBR no son una especificación contractual.","note":"La apariencia gráfica no modifica ni confirma la especificación física del material."} | {"elementId":"found_0904_36db625c917a9f","ifcGuid":"3tTXetFibMVhH2cxskbvUV","ifcClass":"IfcSlab","buildingId":"process_plant","buildingName":"Zona de separación de aire","sourceDocumentId":"LHD2609-JG00100-20260904","sourceRepresentationKind":"foundation"} | {"profileId":"grout_ha35","name":"Grout HA-35 sin retracción","status":"criterio_visual","basis":"Interpretación visual del material documental; el acabado, tono y parámetros PBR no son una especificación contractual.","physicalMaterialUnchanged":true} | WE442-PLAN | 27B6/27BC, 27B6/27BD, 27B6/E6A3, 28D71 | Mortero HA-35 de alta resistencia sin retracción | 0.15 | 0.2 | 0.18 | 0.009 | Sección y contornos del fabricante; incidencias conservadas | Grout HA-35 sin retracción | found_0904_36db625c917a9f | documentado | Capa superior de 50 mm expresada en las secciones del fabricante | 0.6 | 0.3 | grout_ha35 | [0.792157,0.776471,0.721569] | 0.94 | Planta: −2,200 m. Sección 6–6: fondo −2,000 m y coronación de losa −1,200 m. Se adopta sección; pendiente de aclaración.
Cimentación del posenfriador WE442-PLAN · mortero DZ6 2 | Mortero HA-35 de alta resistencia sin retracción | 0.63527 | 0.378926 | 0.05 | 286.25 | 286.3 | 0.45 | 0.009 | {"documentId":"LHD2609-JG00100-20260904","title":"Cimentaciones de equipos y pedestales del fabricante · revisión recibida 04/09/2026","date":"2026-09-04","sheet":"6–6","fileName":"LHD2609-JG00100_20260904.dwg","revisionCaveat":"Fecha de revisión tomada del nombre recibido; cajetines internos mantienen 02/07/2026 y algunos textos de plantilla.","sourceFileSha256":"b42eb027b7bc0b14c38d1d13514f4899b58a732aa8d0ba2ccf10fa2fc3192890"} | {"name":"Mortero HA-35 de alta resistencia sin retracción","status":"documentado","source":"Capa superior de 50 mm expresada en las secciones del fabricante"} | {"documented":[{"label":"Extensión local X","value":0.6,"unit":"m","source":"27B6/27BC, 27B6/27BD, 27B6/E6A3, 28D71","status":"derivada del contorno CAD"},{"label":"Extensión local Y","value":0.3,"unit":"m","source":"27B6/27BC, 27B6/27BD, 27B6/E6A3, 28D71","status":"derivada del contorno CAD"},{"label":"Cota inferior relativa adoptada","value":0.15,"unit":"m","source":"6–6","status":"interpretación con conflicto conservado"},{"label":"Cota superior relativa adoptada","value":0.2,"unit":"m","source":"6–6","status":"documentada / separación por material"}],"geometry":[{"label":"Extensión de la malla en X","value":0.6352699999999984,"unit":"m","source":"Geometría releída del IFC; datum absoluto de proceso provisional","status":"derivado"},{"label":"Extensión de la malla en Y","value":0.3789259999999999,"unit":"m","source":"Geometría releída del IFC; datum absoluto de proceso provisional","status":"derivado"},{"label":"Extensión de la malla en Z","value":0.050000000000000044,"unit":"m","source":"Geometría releída del IFC; datum absoluto de proceso provisional","status":"derivado"},{"label":"Cota inferior de visualización","value":286.25,"unit":"m","source":"Geometría releída del IFC; datum absoluto de proceso provisional","status":"derivado"},{"label":"Cota superior de visualización","value":286.3,"unit":"m","source":"Geometría releída del IFC; datum absoluto de proceso provisional","status":"derivado"}]} | ["Planta: −2,200 m. Sección 6–6: fondo −2,000 m y coronación de losa −1,200 m. Se adopta sección; pendiente de aclaración."] | {"Cota inferior relativa (m)":0.15,"Cota superior relativa (m)":0.2,"Cero absoluto de visualización (m)":286.1,"Estado del cero absoluto":"Provisional","Criterio":"Las cotas relativas proceden del dibujo; la equivalencia absoluta no está confirmada."} | F-WE442-PLAN | ["WE442-PLAN"] | [] | 6–6 | ["27B6/27BC","27B6/27BD","27B6/E6A3","28D71"] | F-WE442-PLAN/Cimentación del posenfriador WE442-PLAN · mortero DZ6 2 | {"boundingBoxM":{"min":[47.895924,47.201277,1.25],"max":[48.531194,47.580203,1.3]},"extentsM":[0.63527,0.378926,0.05],"meshSurfaceM2":0.45,"meshVolumeM3":0.009,"closedSolid":true,"basis":"Magnitudes de las mallas representadas, no cantidades certificadas de obra, compra o fabricación. Las partes pueden compartir superficies; no se suman como un despiece de materiales."} | {"profileId":"grout_ha35","name":"Grout HA-35 sin retracción","materialName":"Mortero HA-35 de alta resistencia sin retracción","physicalMaterialStatus":"documentado","physicalMaterialSource":"Capa superior de 50 mm expresada en las secciones del fabricante","appearanceStatus":"criterio_visual","appearanceBasis":"Interpretación visual del material documental; el acabado, tono y parámetros PBR no son una especificación contractual.","note":"La apariencia gráfica no modifica ni confirma la especificación física del material."} | {"elementId":"found_0904_bc31102c2a4499","ifcGuid":"1LU59CHgjVFe_4FckXhBQ$","ifcClass":"IfcSlab","buildingId":"process_plant","buildingName":"Zona de separación de aire","sourceDocumentId":"LHD2609-JG00100-20260904","sourceRepresentationKind":"foundation"} | {"profileId":"grout_ha35","name":"Grout HA-35 sin retracción","status":"criterio_visual","basis":"Interpretación visual del material documental; el acabado, tono y parámetros PBR no son una especificación contractual.","physicalMaterialUnchanged":true} | WE442-PLAN | 27B6/27BC, 27B6/27BD, 27B6/E6A3, 28D71 | Mortero HA-35 de alta resistencia sin retracción | 0.15 | 0.2 | 0.18 | 0.009 | Sección y contornos del fabricante; incidencias conservadas | Grout HA-35 sin retracción | found_0904_bc31102c2a4499 | documentado | Capa superior de 50 mm expresada en las secciones del fabricante | 0.6 | 0.3 | grout_ha35 | [0.792157,0.776471,0.721569] | 0.94 | Planta: −2,200 m. Sección 6–6: fondo −2,000 m y coronación de losa −1,200 m. Se adopta sección; pendiente de aclaración.
Cimentación del depósito SV1801A · capa de limpieza | Hormigón de limpieza HA-20 | 4.99994 | 4.99994 | 0.1 | 284 | 284.1 | 40.8341 | 1.96317 | {"documentId":"LHD2609-JG00100-20260904","title":"Cimentaciones de equipos y pedestales del fabricante · revisión recibida 04/09/2026","date":"2026-09-04","sheet":"7–7","fileName":"LHD2609-JG00100_20260904.dwg","revisionCaveat":"Fecha de revisión tomada del nombre recibido; cajetines internos mantienen 02/07/2026 y algunos textos de plantilla.","sourceFileSha256":"b42eb027b7bc0b14c38d1d13514f4899b58a732aa8d0ba2ccf10fa2fc3192890"} | {"name":"Hormigón de limpieza HA-20","status":"documentado","source":"Secciones del fabricante: capa de limpieza de 100 mm; nota 2CED5"} | {"documented":[{"label":"Extensión local X","value":5.000027,"unit":"m","source":"254C/2589, 254C/2554, 1FEB7","status":"derivada del contorno CAD"},{"label":"Extensión local Y","value":5.000027,"unit":"m","source":"254C/2589, 254C/2554, 1FEB7","status":"derivada del contorno CAD"},{"label":"Cota inferior relativa adoptada","value":-2.1,"unit":"m","source":"7–7","status":"interpretación con conflicto conservado"},{"label":"Cota superior relativa adoptada","value":-2,"unit":"m","source":"7–7","status":"documentada / separación por material"}],"geometry":[{"label":"Extensión de la malla en X","value":4.999943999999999,"unit":"m","source":"Geometría releída del IFC; datum absoluto de proceso provisional","status":"derivado"},{"label":"Extensión de la malla en Y","value":4.999944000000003,"unit":"m","source":"Geometría releída del IFC; datum absoluto de proceso provisional","status":"derivado"},{"label":"Extensión de la malla en Z","value":0.09999999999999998,"unit":"m","source":"Geometría releída del IFC; datum absoluto de proceso provisional","status":"derivado"},{"label":"Cota inferior de visualización","value":284.0,"unit":"m","source":"Geometría releída del IFC; datum absoluto de proceso provisional","status":"derivado"},{"label":"Cota superior de visualización","value":284.1,"unit":"m","source":"Geometría releída del IFC; datum absoluto de proceso provisional","status":"derivado"}]} | ["La planta contiene una cota de losa distinta de la sección. Sección 7–7 adoptada: fondo −2,000 m, coronación de losa −1,000 m; apoyos acabados +0,500 m."] | {"Cota inferior relativa (m)":-2.1,"Cota superior relativa (m)":-2,"Cero absoluto de visualización (m)":286.1,"Estado del cero absoluto":"Provisional","Criterio":"Las cotas relativas proceden del dibujo; la equivalencia absoluta no está confirmada."} | F-SV1801A | ["SV1801A"] | [] | 7–7 | ["254C/2589","254C/2554","1FEB7"] | F-SV1801A/Cimentación del depósito SV1801A · capa de limpieza | {"boundingBoxM":{"min":[33.877012,30.014048,-1.0],"max":[38.876956,35.013992,-0.9]},"extentsM":[4.999944,4.999944,0.1],"meshSurfaceM2":40.834054,"meshVolumeM3":1.963166,"closedSolid":true,"basis":"Magnitudes de las mallas representadas, no cantidades certificadas de obra, compra o fabricación. Las partes pueden compartir superficies; no se suman como un despiece de materiales."} | {"profileId":"concrete_ha20","name":"Hormigón de limpieza HA-20","materialName":"Hormigón de limpieza HA-20","physicalMaterialStatus":"documentado","physicalMaterialSource":"Secciones del fabricante: capa de limpieza de 100 mm; nota 2CED5","appearanceStatus":"criterio_visual","appearanceBasis":"Interpretación visual del material documental; el acabado, tono y parámetros PBR no son una especificación contractual.","note":"La apariencia gráfica no modifica ni confirma la especificación física del material."} | {"elementId":"found_0904_05e45d36ea4f96","ifcGuid":"0$1DtVwcHV_eltzVfb4Zu6","ifcClass":"IfcSlab","buildingId":"process_plant","buildingName":"Zona de separación de aire","sourceDocumentId":"LHD2609-JG00100-20260904","sourceRepresentationKind":"foundation"} | {"profileId":"concrete_ha20","name":"Hormigón de limpieza HA-20","status":"criterio_visual","basis":"Interpretación visual del material documental; el acabado, tono y parámetros PBR no son una especificación contractual.","physicalMaterialUnchanged":true} | SV1801A | 254C/2589, 254C/2554, 1FEB7 | Hormigón de limpieza HA-20 | -2.1 | -2 | 19.6317 | 1.96317 | Sección y contornos del fabricante; incidencias conservadas | Hormigón de limpieza HA-20 | found_0904_05e45d36ea4f96 | documentado | Secciones del fabricante: capa de limpieza de 100 mm; nota 2CED5 | 5.00003 | 5.00003 | concrete_ha20 | [0.721569,0.709804,0.658824] | 0.98 | La planta contiene una cota de losa distinta de la sección. Sección 7–7 adoptada: fondo −2,000 m, coronación de losa −1,000 m; apoyos acabados +0,500 m.
Cimentación del depósito SV1801A · mortero de apoyo 1 | Mortero HA-35 de alta resistencia sin retracción | 1.20051 | 1.18125 | 0.05 | 286.55 | 286.6 | 1.61 | 0.036 | {"documentId":"LHD2609-JG00100-20260904","title":"Cimentaciones de equipos y pedestales del fabricante · revisión recibida 04/09/2026","date":"2026-09-04","sheet":"7–7","fileName":"LHD2609-JG00100_20260904.dwg","revisionCaveat":"Fecha de revisión tomada del nombre recibido; cajetines internos mantienen 02/07/2026 y algunos textos de plantilla.","sourceFileSha256":"b42eb027b7bc0b14c38d1d13514f4899b58a732aa8d0ba2ccf10fa2fc3192890"} | {"name":"Mortero HA-35 de alta resistencia sin retracción","status":"documentado","source":"Capa superior de 50 mm expresada en las secciones del fabricante"} | {"documented":[{"label":"Extensión local X","value":1.202082,"unit":"m","source":"254C/2589, 254C/2554, 1FEB7","status":"derivada del contorno CAD"},{"label":"Extensión local Y","value":1.202082,"unit":"m","source":"254C/2589, 254C/2554, 1FEB7","status":"derivada del contorno CAD"},{"label":"Cota inferior relativa adoptada","value":0.45,"unit":"m","source":"7–7","status":"interpretación con conflicto conservado"},{"label":"Cota superior relativa adoptada","value":0.5,"unit":"m","source":"7–7","status":"documentada / separación por material"}],"geometry":[{"label":"Extensión de la malla en X","value":1.2005099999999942,"unit":"m","source":"Geometría releída del IFC; datum absoluto de proceso provisional","status":"derivado"},{"label":"Extensión de la malla en Y","value":1.181249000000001,"unit":"m","source":"Geometría releída del IFC; datum absoluto de proceso provisional","status":"derivado"},{"label":"Extensión de la malla en Z","value":0.050000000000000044,"unit":"m","source":"Geometría releída del IFC; datum absoluto de proceso provisional","status":"derivado"},{"label":"Cota inferior de visualización","value":286.55,"unit":"m","source":"Geometría releída del IFC; datum absoluto de proceso provisional","status":"derivado"},{"label":"Cota superior de visualización","value":286.6,"unit":"m","source":"Geometría releída del IFC; datum absoluto de proceso provisional","status":"derivado"}]} | ["La planta contiene una cota de losa distinta de la sección. Sección 7–7 adoptada: fondo −2,000 m, coronación de losa −1,000 m; apoyos acabados +0,500 m."] | {"Cota inferior relativa (m)":0.45,"Cota superior relativa (m)":0.5,"Cero absoluto de visualización (m)":286.1,"Estado del cero absoluto":"Provisional","Criterio":"Las cotas relativas proceden del dibujo; la equivalencia absoluta no está confirmada."} | F-SV1801A | ["SV1801A"] | [] | 7–7 | ["254C/2589","254C/2554","1FEB7"] | F-SV1801A/Cimentación del depósito SV1801A · mortero de apoyo 1 | {"boundingBoxM":{"min":[37.06759,32.90221,1.55],"max":[38.2681,34.083459,1.6]},"extentsM":[1.20051,1.181249,0.05],"meshSurfaceM2":1.610001,"meshVolumeM3":0.036,"closedSolid":true,"basis":"Magnitudes de las mallas representadas, no cantidades certificadas de obra, compra o fabricación. Las partes pueden compartir superficies; no se suman como un despiece de materiales."} | {"profileId":"grout_ha35","name":"Grout HA-35 sin retracción","materialName":"Mortero HA-35 de alta resistencia sin retracción","physicalMaterialStatus":"documentado","physicalMaterialSource":"Capa superior de 50 mm expresada en las secciones del fabricante","appearanceStatus":"criterio_visual","appearanceBasis":"Interpretación visual del material documental; el acabado, tono y parámetros PBR no son una especificación contractual.","note":"La apariencia gráfica no modifica ni confirma la especificación física del material."} | {"elementId":"found_0904_79cb89b98841f0","ifcGuid":"2Upe8Xs3HOWu1WbVUPGH$r","ifcClass":"IfcSlab","buildingId":"process_plant","buildingName":"Zona de separación de aire","sourceDocumentId":"LHD2609-JG00100-20260904","sourceRepresentationKind":"foundation"} | {"profileId":"grout_ha35","name":"Grout HA-35 sin retracción","status":"criterio_visual","basis":"Interpretación visual del material documental; el acabado, tono y parámetros PBR no son una especificación contractual.","physicalMaterialUnchanged":true} | SV1801A | 254C/2589, 254C/2554, 1FEB7 | Mortero HA-35 de alta resistencia sin retracción | 0.45 | 0.5 | 0.72 | 0.036 | Sección y contornos del fabricante; incidencias conservadas | Grout HA-35 sin retracción | found_0904_79cb89b98841f0 | documentado | Capa superior de 50 mm expresada en las secciones del fabricante | 1.20208 | 1.20208 | grout_ha35 | [0.792157,0.776471,0.721569] | 0.94 | La planta contiene una cota de losa distinta de la sección. Sección 7–7 adoptada: fondo −2,000 m, coronación de losa −1,000 m; apoyos acabados +0,500 m.
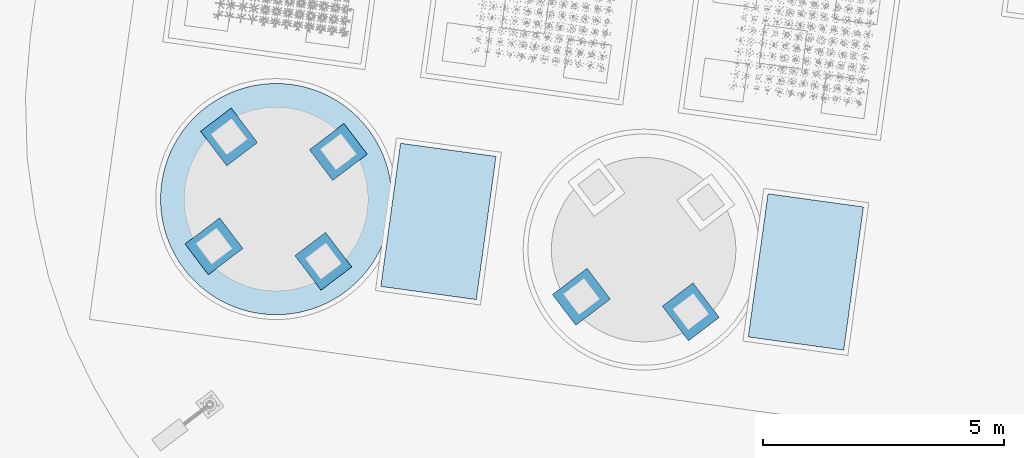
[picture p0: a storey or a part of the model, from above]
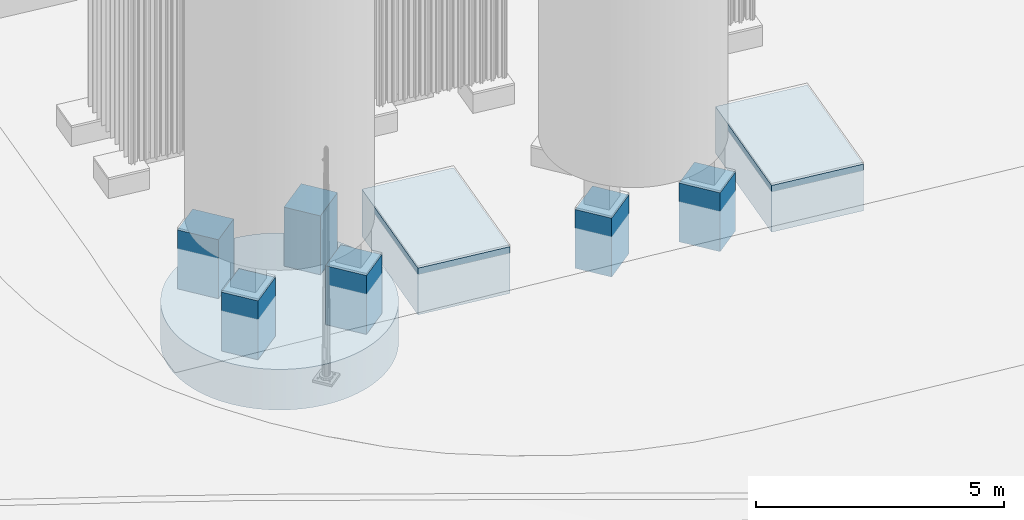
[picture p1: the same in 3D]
Properties of the parts of a building model (IFC4), part 104 of 134

# IfcSlab: Cimentación industrial (108)
Name | Material | Extensión de la malla en X (m) = ExtensionX (m) | Extensión de la malla en Y (m) = ExtensionY (m) | Extensión de la malla en Z (m) = ExtensionZ (m) = Espesor o altura real de sección (m) | Cota inferior de visualización (m) | Cota superior de visualización (m) | SuperficieDeLaMalla (m2) | VolumenGeometrico (m3) | JH_InformacionBIM, source = DocumentoFuente | material | dimensions | issues = IncidenciasPendientes | positioning = PosicionYEstado | assemblyId = Conjunto de cimentación | equipmentIds | supportPositionIds | sectionRef = Sección de referencia | sourceCadHandles | stableElementKey | geometryMetrics | materialAppearance | visualizationIdentity | appearance | Equipos asociados | Identificadores CAD de referencia | JH_Trazabilidad, Material = name | Cota inferior relativa (m) = Cota inferior relativa adoptada (m) | Cota superior relativa (m) = Cota superior relativa adoptada (m) | Área de planta (m²) | Volumen geométrico (m³) | Estado de la geometría | Acabado de visualización = Acabado | Identificador | status | JH_EvidenciaDeMaterial, source | Extensión local X (m) | Extensión local Y (m) | Perfil | ColorRGB | Rugosidad | Incidencias de origen
Cimentación del depósito SV1801A · mortero de apoyo 2 | Mortero HA-35 de alta resistencia sin retracción | 1.18125 | 1.20051 | 0.05 | 286.55 | 286.6 | 1.61 | 0.036 | {"documentId":"LHD2609-JG00100-20260904","title":"Cimentaciones de equipos y pedestales del fabricante · revisión recibida 04/09/2026","date":"2026-09-04","sheet":"7–7","fileName":"LHD2609-JG00100_20260904.dwg","revisionCaveat":"Fecha de revisión tomada del nombre recibido; cajetines internos mantienen 02/07/2026 y algunos textos de plantilla.","sourceFileSha256":"b42eb027b7bc0b14c38d1d13514f4899b58a732aa8d0ba2ccf10fa2fc3192890"} | {"name":"Mortero HA-35 de alta resistencia sin retracción","status":"documentado","source":"Capa superior de 50 mm expresada en las secciones del fabricante"} | {"documented":[{"label":"Extensión local X","value":1.202082,"unit":"m","source":"254C/2589, 254C/2554, 1FEB7","status":"derivada del contorno CAD"},{"label":"Extensión local Y","value":1.202082,"unit":"m","source":"254C/2589, 254C/2554, 1FEB7","status":"derivada del contorno CAD"},{"label":"Cota inferior relativa adoptada","value":0.45,"unit":"m","source":"7–7","status":"interpretación con conflicto conservado"},{"label":"Cota superior relativa adoptada","value":0.5,"unit":"m","source":"7–7","status":"documentada / separación por material"}],"geometry":[{"label":"Extensión de la malla en X","value":1.181249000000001,"unit":"m","source":"Geometría releída del IFC; datum absoluto de proceso provisional","status":"derivado"},{"label":"Extensión de la malla en Y","value":1.2005110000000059,"unit":"m","source":"Geometría releída del IFC; datum absoluto de proceso provisional","status":"derivado"},{"label":"Extensión de la malla en Z","value":0.050000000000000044,"unit":"m","source":"Geometría releída del IFC; datum absoluto de proceso provisional","status":"derivado"},{"label":"Cota inferior de visualización","value":286.55,"unit":"m","source":"Geometría releída del IFC; datum absoluto de proceso provisional","status":"derivado"},{"label":"Cota superior de visualización","value":286.6,"unit":"m","source":"Geometría releída del IFC; datum absoluto de proceso provisional","status":"derivado"}]} | ["La planta contiene una cota de losa distinta de la sección. Sección 7–7 adoptada: fondo −2,000 m, coronación de losa −1,000 m; apoyos acabados +0,500 m."] | {"Cota inferior relativa (m)":0.45,"Cota superior relativa (m)":0.5,"Cero absoluto de visualización (m)":286.1,"Estado del cero absoluto":"Provisional","Criterio":"Las cotas relativas proceden del dibujo; la equivalencia absoluta no está confirmada."} | F-SV1801A | ["SV1801A"] | [] | 7–7 | ["254C/2589","254C/2554","1FEB7"] | F-SV1801A/Cimentación del depósito SV1801A · mortero de apoyo 2 | {"boundingBoxM":{"min":[34.807545,33.204626,1.55],"max":[35.988794,34.405137,1.6]},"extentsM":[1.181249,1.200511,0.05],"meshSurfaceM2":1.610002,"meshVolumeM3":0.036,"closedSolid":true,"basis":"Magnitudes de las mallas representadas, no cantidades certificadas de obra, compra o fabricación. Las partes pueden compartir superficies; no se suman como un despiece de materiales."} | {"profileId":"grout_ha35","name":"Grout HA-35 sin retracción","materialName":"Mortero HA-35 de alta resistencia sin retracción","physicalMaterialStatus":"documentado","physicalMaterialSource":"Capa superior de 50 mm expresada en las secciones del fabricante","appearanceStatus":"criterio_visual","appearanceBasis":"Interpretación visual del material documental; el acabado, tono y parámetros PBR no son una especificación contractual.","note":"La apariencia gráfica no modifica ni confirma la especificación física del material."} | {"elementId":"found_0904_625ff173a269a3","ifcGuid":"09xRyYLCbOP9ErBEN4bYYw","ifcClass":"IfcSlab","buildingId":"process_plant","buildingName":"Zona de separación de aire","sourceDocumentId":"LHD2609-JG00100-20260904","sourceRepresentationKind":"foundation"} | {"profileId":"grout_ha35","name":"Grout HA-35 sin retracción","status":"criterio_visual","basis":"Interpretación visual del material documental; el acabado, tono y parámetros PBR no son una especificación contractual.","physicalMaterialUnchanged":true} | SV1801A | 254C/2589, 254C/2554, 1FEB7 | Mortero HA-35 de alta resistencia sin retracción | 0.45 | 0.5 | 0.72 | 0.036 | Sección y contornos del fabricante; incidencias conservadas | Grout HA-35 sin retracción | found_0904_625ff173a269a3 | documentado | Capa superior de 50 mm expresada en las secciones del fabricante | 1.20208 | 1.20208 | grout_ha35 | [0.792157,0.776471,0.721569] | 0.94 | La planta contiene una cota de losa distinta de la sección. Sección 7–7 adoptada: fondo −2,000 m, coronación de losa −1,000 m; apoyos acabados +0,500 m.
Cimentación del depósito SV1801A · mortero de apoyo 3 | Mortero HA-35 de alta resistencia sin retracción | 1.18125 | 1.20051 | 0.05 | 286.55 | 286.6 | 1.61 | 0.036 | {"documentId":"LHD2609-JG00100-20260904","title":"Cimentaciones de equipos y pedestales del fabricante · revisión recibida 04/09/2026","date":"2026-09-04","sheet":"7–7","fileName":"LHD2609-JG00100_20260904.dwg","revisionCaveat":"Fecha de revisión tomada del nombre recibido; cajetines internos mantienen 02/07/2026 y algunos textos de plantilla.","sourceFileSha256":"b42eb027b7bc0b14c38d1d13514f4899b58a732aa8d0ba2ccf10fa2fc3192890"} | {"name":"Mortero HA-35 de alta resistencia sin retracción","status":"documentado","source":"Capa superior de 50 mm expresada en las secciones del fabricante"} | {"documented":[{"label":"Extensión local X","value":1.202082,"unit":"m","source":"254C/2589, 254C/2554, 1FEB7","status":"derivada del contorno CAD"},{"label":"Extensión local Y","value":1.202082,"unit":"m","source":"254C/2589, 254C/2554, 1FEB7","status":"derivada del contorno CAD"},{"label":"Cota inferior relativa adoptada","value":0.45,"unit":"m","source":"7–7","status":"interpretación con conflicto conservado"},{"label":"Cota superior relativa adoptada","value":0.5,"unit":"m","source":"7–7","status":"documentada / separación por material"}],"geometry":[{"label":"Extensión de la malla en X","value":1.181249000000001,"unit":"m","source":"Geometría releída del IFC; datum absoluto de proceso provisional","status":"derivado"},{"label":"Extensión de la malla en Y","value":1.2005100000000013,"unit":"m","source":"Geometría releída del IFC; datum absoluto de proceso provisional","status":"derivado"},{"label":"Extensión de la malla en Z","value":0.050000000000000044,"unit":"m","source":"Geometría releída del IFC; datum absoluto de proceso provisional","status":"derivado"},{"label":"Cota inferior de visualización","value":286.55,"unit":"m","source":"Geometría releída del IFC; datum absoluto de proceso provisional","status":"derivado"},{"label":"Cota superior de visualización","value":286.6,"unit":"m","source":"Geometría releída del IFC; datum absoluto de proceso provisional","status":"derivado"}]} | ["La planta contiene una cota de losa distinta de la sección. Sección 7–7 adoptada: fondo −2,000 m, coronación de losa −1,000 m; apoyos acabados +0,500 m."] | {"Cota inferior relativa (m)":0.45,"Cota superior relativa (m)":0.5,"Cero absoluto de visualización (m)":286.1,"Estado del cero absoluto":"Provisional","Criterio":"Las cotas relativas proceden del dibujo; la equivalencia absoluta no está confirmada."} | F-SV1801A | ["SV1801A"] | [] | 7–7 | ["254C/2589","254C/2554","1FEB7"] | F-SV1801A/Cimentación del depósito SV1801A · mortero de apoyo 3 | {"boundingBoxM":{"min":[36.765174,30.622904,1.55],"max":[37.946423,31.823414,1.6]},"extentsM":[1.181249,1.20051,0.05],"meshSurfaceM2":1.610001,"meshVolumeM3":0.036,"closedSolid":true,"basis":"Magnitudes de las mallas representadas, no cantidades certificadas de obra, compra o fabricación. Las partes pueden compartir superficies; no se suman como un despiece de materiales."} | {"profileId":"grout_ha35","name":"Grout HA-35 sin retracción","materialName":"Mortero HA-35 de alta resistencia sin retracción","physicalMaterialStatus":"documentado","physicalMaterialSource":"Capa superior de 50 mm expresada en las secciones del fabricante","appearanceStatus":"criterio_visual","appearanceBasis":"Interpretación visual del material documental; el acabado, tono y parámetros PBR no son una especificación contractual.","note":"La apariencia gráfica no modifica ni confirma la especificación física del material."} | {"elementId":"found_0904_1765e5f8dc4f36","ifcGuid":"3EUvm_rT5NwvRiZ1Q8$do6","ifcClass":"IfcSlab","buildingId":"process_plant","buildingName":"Zona de separación de aire","sourceDocumentId":"LHD2609-JG00100-20260904","sourceRepresentationKind":"foundation"} | {"profileId":"grout_ha35","name":"Grout HA-35 sin retracción","status":"criterio_visual","basis":"Interpretación visual del material documental; el acabado, tono y parámetros PBR no son una especificación contractual.","physicalMaterialUnchanged":true} | SV1801A | 254C/2589, 254C/2554, 1FEB7 | Mortero HA-35 de alta resistencia sin retracción | 0.45 | 0.5 | 0.72 | 0.036 | Sección y contornos del fabricante; incidencias conservadas | Grout HA-35 sin retracción | found_0904_1765e5f8dc4f36 | documentado | Capa superior de 50 mm expresada en las secciones del fabricante | 1.20208 | 1.20208 | grout_ha35 | [0.792157,0.776471,0.721569] | 0.94 | La planta contiene una cota de losa distinta de la sección. Sección 7–7 adoptada: fondo −2,000 m, coronación de losa −1,000 m; apoyos acabados +0,500 m.
Cimentación del depósito SV1801A · mortero de apoyo 4 | Mortero HA-35 de alta resistencia sin retracción | 1.20051 | 1.18125 | 0.05 | 286.55 | 286.6 | 1.61 | 0.036 | {"documentId":"LHD2609-JG00100-20260904","title":"Cimentaciones de equipos y pedestales del fabricante · revisión recibida 04/09/2026","date":"2026-09-04","sheet":"7–7","fileName":"LHD2609-JG00100_20260904.dwg","revisionCaveat":"Fecha de revisión tomada del nombre recibido; cajetines internos mantienen 02/07/2026 y algunos textos de plantilla.","sourceFileSha256":"b42eb027b7bc0b14c38d1d13514f4899b58a732aa8d0ba2ccf10fa2fc3192890"} | {"name":"Mortero HA-35 de alta resistencia sin retracción","status":"documentado","source":"Capa superior de 50 mm expresada en las secciones del fabricante"} | {"documented":[{"label":"Extensión local X","value":1.202082,"unit":"m","source":"254C/2589, 254C/2554, 1FEB7","status":"derivada del contorno CAD"},{"label":"Extensión local Y","value":1.202082,"unit":"m","source":"254C/2589, 254C/2554, 1FEB7","status":"derivada del contorno CAD"},{"label":"Cota inferior relativa adoptada","value":0.45,"unit":"m","source":"7–7","status":"interpretación con conflicto conservado"},{"label":"Cota superior relativa adoptada","value":0.5,"unit":"m","source":"7–7","status":"documentada / separación por material"}],"geometry":[{"label":"Extensión de la malla en X","value":1.2005099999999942,"unit":"m","source":"Geometría releída del IFC; datum absoluto de proceso provisional","status":"derivado"},{"label":"Extensión de la malla en Y","value":1.181248,"unit":"m","source":"Geometría releída del IFC; datum absoluto de proceso provisional","status":"derivado"},{"label":"Extensión de la malla en Z","value":0.050000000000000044,"unit":"m","source":"Geometría releída del IFC; datum absoluto de proceso provisional","status":"derivado"},{"label":"Cota inferior de visualización","value":286.55,"unit":"m","source":"Geometría releída del IFC; datum absoluto de proceso provisional","status":"derivado"},{"label":"Cota superior de visualización","value":286.6,"unit":"m","source":"Geometría releída del IFC; datum absoluto de proceso provisional","status":"derivado"}]} | ["La planta contiene una cota de losa distinta de la sección. Sección 7–7 adoptada: fondo −2,000 m, coronación de losa −1,000 m; apoyos acabados +0,500 m."] | {"Cota inferior relativa (m)":0.45,"Cota superior relativa (m)":0.5,"Cero absoluto de visualización (m)":286.1,"Estado del cero absoluto":"Provisional","Criterio":"Las cotas relativas proceden del dibujo; la equivalencia absoluta no está confirmada."} | F-SV1801A | ["SV1801A"] | [] | 7–7 | ["254C/2589","254C/2554","1FEB7"] | F-SV1801A/Cimentación del depósito SV1801A · mortero de apoyo 4 | {"boundingBoxM":{"min":[34.485868,30.944582,1.55],"max":[35.686378,32.12583,1.6]},"extentsM":[1.20051,1.181248,0.05],"meshSurfaceM2":1.61,"meshVolumeM3":0.036,"closedSolid":true,"basis":"Magnitudes de las mallas representadas, no cantidades certificadas de obra, compra o fabricación. Las partes pueden compartir superficies; no se suman como un despiece de materiales."} | {"profileId":"grout_ha35","name":"Grout HA-35 sin retracción","materialName":"Mortero HA-35 de alta resistencia sin retracción","physicalMaterialStatus":"documentado","physicalMaterialSource":"Capa superior de 50 mm expresada en las secciones del fabricante","appearanceStatus":"criterio_visual","appearanceBasis":"Interpretación visual del material documental; el acabado, tono y parámetros PBR no son una especificación contractual.","note":"La apariencia gráfica no modifica ni confirma la especificación física del material."} | {"elementId":"found_0904_655b3ae9ebe287","ifcGuid":"2jmj8w4WvIZOpudeU4xlNt","ifcClass":"IfcSlab","buildingId":"process_plant","buildingName":"Zona de separación de aire","sourceDocumentId":"LHD2609-JG00100-20260904","sourceRepresentationKind":"foundation"} | {"profileId":"grout_ha35","name":"Grout HA-35 sin retracción","status":"criterio_visual","basis":"Interpretación visual del material documental; el acabado, tono y parámetros PBR no son una especificación contractual.","physicalMaterialUnchanged":true} | SV1801A | 254C/2589, 254C/2554, 1FEB7 | Mortero HA-35 de alta resistencia sin retracción | 0.45 | 0.5 | 0.72 | 0.036 | Sección y contornos del fabricante; incidencias conservadas | Grout HA-35 sin retracción | found_0904_655b3ae9ebe287 | documentado | Capa superior de 50 mm expresada en las secciones del fabricante | 1.20208 | 1.20208 | grout_ha35 | [0.792157,0.776471,0.721569] | 0.94 | La planta contiene una cota de losa distinta de la sección. Sección 7–7 adoptada: fondo −2,000 m, coronación de losa −1,000 m; apoyos acabados +0,500 m.
Cimentación del depósito SV1801B · capa de limpieza | Hormigón de limpieza HA-20 | 4.99994 | 4.99994 | 0.1 | 284 | 284.1 | 40.8341 | 1.96317 | {"documentId":"LHD2609-JG00100-20260904","title":"Cimentaciones de equipos y pedestales del fabricante · revisión recibida 04/09/2026","date":"2026-09-04","sheet":"7–7","fileName":"LHD2609-JG00100_20260904.dwg","revisionCaveat":"Fecha de revisión tomada del nombre recibido; cajetines internos mantienen 02/07/2026 y algunos textos de plantilla.","sourceFileSha256":"b42eb027b7bc0b14c38d1d13514f4899b58a732aa8d0ba2ccf10fa2fc3192890"} | {"name":"Hormigón de limpieza HA-20","status":"documentado","source":"Secciones del fabricante: capa de limpieza de 100 mm; nota 2CED5"} | {"documented":[{"label":"Extensión local X","value":5.000027,"unit":"m","source":"26E2/2589, 26E2/2554, 1FEB7","status":"derivada del contorno CAD"},{"label":"Extensión local Y","value":5.000027,"unit":"m","source":"26E2/2589, 26E2/2554, 1FEB7","status":"derivada del contorno CAD"},{"label":"Cota inferior relativa adoptada","value":-2.1,"unit":"m","source":"7–7","status":"interpretación con conflicto conservado"},{"label":"Cota superior relativa adoptada","value":-2,"unit":"m","source":"7–7","status":"documentada / separación por material"}],"geometry":[{"label":"Extensión de la malla en X","value":4.999943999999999,"unit":"m","source":"Geometría releída del IFC; datum absoluto de proceso provisional","status":"derivado"},{"label":"Extensión de la malla en Y","value":4.999943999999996,"unit":"m","source":"Geometría releída del IFC; datum absoluto de proceso provisional","status":"derivado"},{"label":"Extensión de la malla en Z","value":0.09999999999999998,"unit":"m","source":"Geometría releída del IFC; datum absoluto de proceso provisional","status":"derivado"},{"label":"Cota inferior de visualización","value":284.0,"unit":"m","source":"Geometría releída del IFC; datum absoluto de proceso provisional","status":"derivado"},{"label":"Cota superior de visualización","value":284.1,"unit":"m","source":"Geometría releída del IFC; datum absoluto de proceso provisional","status":"derivado"}]} | ["La planta contiene una cota de losa distinta de la sección. Sección 7–7 adoptada: fondo −2,000 m, coronación de losa −1,000 m; apoyos acabados +0,500 m."] | {"Cota inferior relativa (m)":-2.1,"Cota superior relativa (m)":-2,"Cero absoluto de visualización (m)":286.1,"Estado del cero absoluto":"Provisional","Criterio":"Las cotas relativas proceden del dibujo; la equivalencia absoluta no está confirmada."} | F-SV1801B | ["SV1801B"] | [] | 7–7 | ["26E2/2589","26E2/2554","1FEB7"] | F-SV1801B/Cimentación del depósito SV1801B · capa de limpieza | {"boundingBoxM":{"min":[41.505254,28.965278,-1.0],"max":[46.505198,33.965222,-0.9]},"extentsM":[4.999944,4.999944,0.1],"meshSurfaceM2":40.834054,"meshVolumeM3":1.963166,"closedSolid":true,"basis":"Magnitudes de las mallas representadas, no cantidades certificadas de obra, compra o fabricación. Las partes pueden compartir superficies; no se suman como un despiece de materiales."} | {"profileId":"concrete_ha20","name":"Hormigón de limpieza HA-20","materialName":"Hormigón de limpieza HA-20","physicalMaterialStatus":"documentado","physicalMaterialSource":"Secciones del fabricante: capa de limpieza de 100 mm; nota 2CED5","appearanceStatus":"criterio_visual","appearanceBasis":"Interpretación visual del material documental; el acabado, tono y parámetros PBR no son una especificación contractual.","note":"La apariencia gráfica no modifica ni confirma la especificación física del material."} | {"elementId":"found_0904_1560ce06c6f620","ifcGuid":"2ek7$mZjXUogX4LX5GXWGY","ifcClass":"IfcSlab","buildingId":"process_plant","buildingName":"Zona de separación de aire","sourceDocumentId":"LHD2609-JG00100-20260904","sourceRepresentationKind":"foundation"} | {"profileId":"concrete_ha20","name":"Hormigón de limpieza HA-20","status":"criterio_visual","basis":"Interpretación visual del material documental; el acabado, tono y parámetros PBR no son una especificación contractual.","physicalMaterialUnchanged":true} | SV1801B | 26E2/2589, 26E2/2554, 1FEB7 | Hormigón de limpieza HA-20 | -2.1 | -2 | 19.6317 | 1.96317 | Sección y contornos del fabricante; incidencias conservadas | Hormigón de limpieza HA-20 | found_0904_1560ce06c6f620 | documentado | Secciones del fabricante: capa de limpieza de 100 mm; nota 2CED5 | 5.00003 | 5.00003 | concrete_ha20 | [0.721569,0.709804,0.658824] | 0.98 | La planta contiene una cota de losa distinta de la sección. Sección 7–7 adoptada: fondo −2,000 m, coronación de losa −1,000 m; apoyos acabados +0,500 m.
Cimentación del depósito SV1801B · mortero de apoyo 1 | Mortero HA-35 de alta resistencia sin retracción | 1.20051 | 1.18125 | 0.05 | 286.55 | 286.6 | 1.61 | 0.036 | {"documentId":"LHD2609-JG00100-20260904","title":"Cimentaciones de equipos y pedestales del fabricante · revisión recibida 04/09/2026","date":"2026-09-04","sheet":"7–7","fileName":"LHD2609-JG00100_20260904.dwg","revisionCaveat":"Fecha de revisión tomada del nombre recibido; cajetines internos mantienen 02/07/2026 y algunos textos de plantilla.","sourceFileSha256":"b42eb027b7bc0b14c38d1d13514f4899b58a732aa8d0ba2ccf10fa2fc3192890"} | {"name":"Mortero HA-35 de alta resistencia sin retracción","status":"documentado","source":"Capa superior de 50 mm expresada en las secciones del fabricante"} | {"documented":[{"label":"Extensión local X","value":1.202082,"unit":"m","source":"26E2/2589, 26E2/2554, 1FEB7","status":"derivada del contorno CAD"},{"label":"Extensión local Y","value":1.202082,"unit":"m","source":"26E2/2589, 26E2/2554, 1FEB7","status":"derivada del contorno CAD"},{"label":"Cota inferior relativa adoptada","value":0.45,"unit":"m","source":"7–7","status":"interpretación con conflicto conservado"},{"label":"Cota superior relativa adoptada","value":0.5,"unit":"m","source":"7–7","status":"documentada / separación por material"}],"geometry":[{"label":"Extensión de la malla en X","value":1.2005109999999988,"unit":"m","source":"Geometría releída del IFC; datum absoluto de proceso provisional","status":"derivado"},{"label":"Extensión de la malla en Y","value":1.181249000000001,"unit":"m","source":"Geometría releída del IFC; datum absoluto de proceso provisional","status":"derivado"},{"label":"Extensión de la malla en Z","value":0.050000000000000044,"unit":"m","source":"Geometría releída del IFC; datum absoluto de proceso provisional","status":"derivado"},{"label":"Cota inferior de visualización","value":286.55,"unit":"m","source":"Geometría releída del IFC; datum absoluto de proceso provisional","status":"derivado"},{"label":"Cota superior de visualización","value":286.6,"unit":"m","source":"Geometría releída del IFC; datum absoluto de proceso provisional","status":"derivado"}]} | ["La planta contiene una cota de losa distinta de la sección. Sección 7–7 adoptada: fondo −2,000 m, coronación de losa −1,000 m; apoyos acabados +0,500 m."] | {"Cota inferior relativa (m)":0.45,"Cota superior relativa (m)":0.5,"Cero absoluto de visualización (m)":286.1,"Estado del cero absoluto":"Provisional","Criterio":"Las cotas relativas proceden del dibujo; la equivalencia absoluta no está confirmada."} | F-SV1801B | ["SV1801B"] | [] | 7–7 | ["26E2/2589","26E2/2554","1FEB7"] | F-SV1801B/Cimentación del depósito SV1801B · mortero de apoyo 1 | {"boundingBoxM":{"min":[44.695832,31.85344,1.55],"max":[45.896343,33.034689,1.6]},"extentsM":[1.200511,1.181249,0.05],"meshSurfaceM2":1.610002,"meshVolumeM3":0.036,"closedSolid":true,"basis":"Magnitudes de las mallas representadas, no cantidades certificadas de obra, compra o fabricación. Las partes pueden compartir superficies; no se suman como un despiece de materiales."} | {"profileId":"grout_ha35","name":"Grout HA-35 sin retracción","materialName":"Mortero HA-35 de alta resistencia sin retracción","physicalMaterialStatus":"documentado","physicalMaterialSource":"Capa superior de 50 mm expresada en las secciones del fabricante","appearanceStatus":"criterio_visual","appearanceBasis":"Interpretación visual del material documental; el acabado, tono y parámetros PBR no son una especificación contractual.","note":"La apariencia gráfica no modifica ni confirma la especificación física del material."} | {"elementId":"found_0904_05dc0b2212108d","ifcGuid":"3zbY5IF$5KCgMEoP1n1BNP","ifcClass":"IfcSlab","buildingId":"process_plant","buildingName":"Zona de separación de aire","sourceDocumentId":"LHD2609-JG00100-20260904","sourceRepresentationKind":"foundation"} | {"profileId":"grout_ha35","name":"Grout HA-35 sin retracción","status":"criterio_visual","basis":"Interpretación visual del material documental; el acabado, tono y parámetros PBR no son una especificación contractual.","physicalMaterialUnchanged":true} | SV1801B | 26E2/2589, 26E2/2554, 1FEB7 | Mortero HA-35 de alta resistencia sin retracción | 0.45 | 0.5 | 0.72 | 0.036 | Sección y contornos del fabricante; incidencias conservadas | Grout HA-35 sin retracción | found_0904_05dc0b2212108d | documentado | Capa superior de 50 mm expresada en las secciones del fabricante | 1.20208 | 1.20208 | grout_ha35 | [0.792157,0.776471,0.721569] | 0.94 | La planta contiene una cota de losa distinta de la sección. Sección 7–7 adoptada: fondo −2,000 m, coronación de losa −1,000 m; apoyos acabados +0,500 m.
Cimentación del depósito SV1801B · mortero de apoyo 2 | Mortero HA-35 de alta resistencia sin retracción | 1.18125 | 1.20051 | 0.05 | 286.55 | 286.6 | 1.61 | 0.036 | {"documentId":"LHD2609-JG00100-20260904","title":"Cimentaciones de equipos y pedestales del fabricante · revisión recibida 04/09/2026","date":"2026-09-04","sheet":"7–7","fileName":"LHD2609-JG00100_20260904.dwg","revisionCaveat":"Fecha de revisión tomada del nombre recibido; cajetines internos mantienen 02/07/2026 y algunos textos de plantilla.","sourceFileSha256":"b42eb027b7bc0b14c38d1d13514f4899b58a732aa8d0ba2ccf10fa2fc3192890"} | {"name":"Mortero HA-35 de alta resistencia sin retracción","status":"documentado","source":"Capa superior de 50 mm expresada en las secciones del fabricante"} | {"documented":[{"label":"Extensión local X","value":1.202082,"unit":"m","source":"26E2/2589, 26E2/2554, 1FEB7","status":"derivada del contorno CAD"},{"label":"Extensión local Y","value":1.202082,"unit":"m","source":"26E2/2589, 26E2/2554, 1FEB7","status":"derivada del contorno CAD"},{"label":"Cota inferior relativa adoptada","value":0.45,"unit":"m","source":"7–7","status":"interpretación con conflicto conservado"},{"label":"Cota superior relativa adoptada","value":0.5,"unit":"m","source":"7–7","status":"documentada / separación por material"}],"geometry":[{"label":"Extensión de la malla en X","value":1.1812479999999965,"unit":"m","source":"Geometría releída del IFC; datum absoluto de proceso provisional","status":"derivado"},{"label":"Extensión de la malla en Y","value":1.2005100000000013,"unit":"m","source":"Geometría releída del IFC; datum absoluto de proceso provisional","status":"derivado"},{"label":"Extensión de la malla en Z","value":0.050000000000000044,"unit":"m","source":"Geometría releída del IFC; datum absoluto de proceso provisional","status":"derivado"},{"label":"Cota inferior de visualización","value":286.55,"unit":"m","source":"Geometría releída del IFC; datum absoluto de proceso provisional","status":"derivado"},{"label":"Cota superior de visualización","value":286.6,"unit":"m","source":"Geometría releída del IFC; datum absoluto de proceso provisional","status":"derivado"}]} | ["La planta contiene una cota de losa distinta de la sección. Sección 7–7 adoptada: fondo −2,000 m, coronación de losa −1,000 m; apoyos acabados +0,500 m."] | {"Cota inferior relativa (m)":0.45,"Cota superior relativa (m)":0.5,"Cero absoluto de visualización (m)":286.1,"Estado del cero absoluto":"Provisional","Criterio":"Las cotas relativas proceden del dibujo; la equivalencia absoluta no está confirmada."} | F-SV1801B | ["SV1801B"] | [] | 7–7 | ["26E2/2589","26E2/2554","1FEB7"] | F-SV1801B/Cimentación del depósito SV1801B · mortero de apoyo 2 | {"boundingBoxM":{"min":[42.435788,32.155856,1.55],"max":[43.617036,33.356366,1.6]},"extentsM":[1.181248,1.20051,0.05],"meshSurfaceM2":1.61,"meshVolumeM3":0.036,"closedSolid":true,"basis":"Magnitudes de las mallas representadas, no cantidades certificadas de obra, compra o fabricación. Las partes pueden compartir superficies; no se suman como un despiece de materiales."} | {"profileId":"grout_ha35","name":"Grout HA-35 sin retracción","materialName":"Mortero HA-35 de alta resistencia sin retracción","physicalMaterialStatus":"documentado","physicalMaterialSource":"Capa superior de 50 mm expresada en las secciones del fabricante","appearanceStatus":"criterio_visual","appearanceBasis":"Interpretación visual del material documental; el acabado, tono y parámetros PBR no son una especificación contractual.","note":"La apariencia gráfica no modifica ni confirma la especificación física del material."} | {"elementId":"found_0904_a3aab55a390f86","ifcGuid":"0nPmN_sKDRqhHt1oknZOPC","ifcClass":"IfcSlab","buildingId":"process_plant","buildingName":"Zona de separación de aire","sourceDocumentId":"LHD2609-JG00100-20260904","sourceRepresentationKind":"foundation"} | {"profileId":"grout_ha35","name":"Grout HA-35 sin retracción","status":"criterio_visual","basis":"Interpretación visual del material documental; el acabado, tono y parámetros PBR no son una especificación contractual.","physicalMaterialUnchanged":true} | SV1801B | 26E2/2589, 26E2/2554, 1FEB7 | Mortero HA-35 de alta resistencia sin retracción | 0.45 | 0.5 | 0.72 | 0.036 | Sección y contornos del fabricante; incidencias conservadas | Grout HA-35 sin retracción | found_0904_a3aab55a390f86 | documentado | Capa superior de 50 mm expresada en las secciones del fabricante | 1.20208 | 1.20208 | grout_ha35 | [0.792157,0.776471,0.721569] | 0.94 | La planta contiene una cota de losa distinta de la sección. Sección 7–7 adoptada: fondo −2,000 m, coronación de losa −1,000 m; apoyos acabados +0,500 m.
Cimentación del depósito SV1801B · mortero de apoyo 3 | Mortero HA-35 de alta resistencia sin retracción | 1.18125 | 1.20051 | 0.05 | 286.55 | 286.6 | 1.61 | 0.036 | {"documentId":"LHD2609-JG00100-20260904","title":"Cimentaciones de equipos y pedestales del fabricante · revisión recibida 04/09/2026","date":"2026-09-04","sheet":"7–7","fileName":"LHD2609-JG00100_20260904.dwg","revisionCaveat":"Fecha de revisión tomada del nombre recibido; cajetines internos mantienen 02/07/2026 y algunos textos de plantilla.","sourceFileSha256":"b42eb027b7bc0b14c38d1d13514f4899b58a732aa8d0ba2ccf10fa2fc3192890"} | {"name":"Mortero HA-35 de alta resistencia sin retracción","status":"documentado","source":"Capa superior de 50 mm expresada en las secciones del fabricante"} | {"documented":[{"label":"Extensión local X","value":1.202082,"unit":"m","source":"26E2/2589, 26E2/2554, 1FEB7","status":"derivada del contorno CAD"},{"label":"Extensión local Y","value":1.202082,"unit":"m","source":"26E2/2589, 26E2/2554, 1FEB7","status":"derivada del contorno CAD"},{"label":"Cota inferior relativa adoptada","value":0.45,"unit":"m","source":"7–7","status":"interpretación con conflicto conservado"},{"label":"Cota superior relativa adoptada","value":0.5,"unit":"m","source":"7–7","status":"documentada / separación por material"}],"geometry":[{"label":"Extensión de la malla en X","value":1.181249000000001,"unit":"m","source":"Geometría releída del IFC; datum absoluto de proceso provisional","status":"derivado"},{"label":"Extensión de la malla en Y","value":1.2005099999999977,"unit":"m","source":"Geometría releída del IFC; datum absoluto de proceso provisional","status":"derivado"},{"label":"Extensión de la malla en Z","value":0.050000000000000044,"unit":"m","source":"Geometría releída del IFC; datum absoluto de proceso provisional","status":"derivado"},{"label":"Cota inferior de visualización","value":286.55,"unit":"m","source":"Geometría releída del IFC; datum absoluto de proceso provisional","status":"derivado"},{"label":"Cota superior de visualización","value":286.6,"unit":"m","source":"Geometría releída del IFC; datum absoluto de proceso provisional","status":"derivado"}]} | ["La planta contiene una cota de losa distinta de la sección. Sección 7–7 adoptada: fondo −2,000 m, coronación de losa −1,000 m; apoyos acabados +0,500 m."] | {"Cota inferior relativa (m)":0.45,"Cota superior relativa (m)":0.5,"Cero absoluto de visualización (m)":286.1,"Estado del cero absoluto":"Provisional","Criterio":"Las cotas relativas proceden del dibujo; la equivalencia absoluta no está confirmada."} | F-SV1801B | ["SV1801B"] | [] | 7–7 | ["26E2/2589","26E2/2554","1FEB7"] | F-SV1801B/Cimentación del depósito SV1801B · mortero de apoyo 3 | {"boundingBoxM":{"min":[44.393416,29.574134,1.55],"max":[45.574665,30.774644,1.6]},"extentsM":[1.181249,1.20051,0.05],"meshSurfaceM2":1.610001,"meshVolumeM3":0.036,"closedSolid":true,"basis":"Magnitudes de las mallas representadas, no cantidades certificadas de obra, compra o fabricación. Las partes pueden compartir superficies; no se suman como un despiece de materiales."} | {"profileId":"grout_ha35","name":"Grout HA-35 sin retracción","materialName":"Mortero HA-35 de alta resistencia sin retracción","physicalMaterialStatus":"documentado","physicalMaterialSource":"Capa superior de 50 mm expresada en las secciones del fabricante","appearanceStatus":"criterio_visual","appearanceBasis":"Interpretación visual del material documental; el acabado, tono y parámetros PBR no son una especificación contractual.","note":"La apariencia gráfica no modifica ni confirma la especificación física del material."} | {"elementId":"found_0904_8f98344bec99e5","ifcGuid":"2ZEUK8c$9RwgczUm25GllB","ifcClass":"IfcSlab","buildingId":"process_plant","buildingName":"Zona de separación de aire","sourceDocumentId":"LHD2609-JG00100-20260904","sourceRepresentationKind":"foundation"} | {"profileId":"grout_ha35","name":"Grout HA-35 sin retracción","status":"criterio_visual","basis":"Interpretación visual del material documental; el acabado, tono y parámetros PBR no son una especificación contractual.","physicalMaterialUnchanged":true} | SV1801B | 26E2/2589, 26E2/2554, 1FEB7 | Mortero HA-35 de alta resistencia sin retracción | 0.45 | 0.5 | 0.72 | 0.036 | Sección y contornos del fabricante; incidencias conservadas | Grout HA-35 sin retracción | found_0904_8f98344bec99e5 | documentado | Capa superior de 50 mm expresada en las secciones del fabricante | 1.20208 | 1.20208 | grout_ha35 | [0.792157,0.776471,0.721569] | 0.94 | La planta contiene una cota de losa distinta de la sección. Sección 7–7 adoptada: fondo −2,000 m, coronación de losa −1,000 m; apoyos acabados +0,500 m.
Cimentación del depósito SV1801B · mortero de apoyo 4 | Mortero HA-35 de alta resistencia sin retracción | 1.20051 | 1.18125 | 0.05 | 286.55 | 286.6 | 1.61 | 0.036 | {"documentId":"LHD2609-JG00100-20260904","title":"Cimentaciones de equipos y pedestales del fabricante · revisión recibida 04/09/2026","date":"2026-09-04","sheet":"7–7","fileName":"LHD2609-JG00100_20260904.dwg","revisionCaveat":"Fecha de revisión tomada del nombre recibido; cajetines internos mantienen 02/07/2026 y algunos textos de plantilla.","sourceFileSha256":"b42eb027b7bc0b14c38d1d13514f4899b58a732aa8d0ba2ccf10fa2fc3192890"} | {"name":"Mortero HA-35 de alta resistencia sin retracción","status":"documentado","source":"Capa superior de 50 mm expresada en las secciones del fabricante"} | {"documented":[{"label":"Extensión local X","value":1.202082,"unit":"m","source":"26E2/2589, 26E2/2554, 1FEB7","status":"derivada del contorno CAD"},{"label":"Extensión local Y","value":1.202082,"unit":"m","source":"26E2/2589, 26E2/2554, 1FEB7","status":"derivada del contorno CAD"},{"label":"Cota inferior relativa adoptada","value":0.45,"unit":"m","source":"7–7","status":"interpretación con conflicto conservado"},{"label":"Cota superior relativa adoptada","value":0.5,"unit":"m","source":"7–7","status":"documentada / separación por material"}],"geometry":[{"label":"Extensión de la malla en X","value":1.2005110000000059,"unit":"m","source":"Geometría releída del IFC; datum absoluto de proceso provisional","status":"derivado"},{"label":"Extensión de la malla en Y","value":1.181249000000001,"unit":"m","source":"Geometría releída del IFC; datum absoluto de proceso provisional","status":"derivado"},{"label":"Extensión de la malla en Z","value":0.050000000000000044,"unit":"m","source":"Geometría releída del IFC; datum absoluto de proceso provisional","status":"derivado"},{"label":"Cota inferior de visualización","value":286.55,"unit":"m","source":"Geometría releída del IFC; datum absoluto de proceso provisional","status":"derivado"},{"label":"Cota superior de visualización","value":286.6,"unit":"m","source":"Geometría releída del IFC; datum absoluto de proceso provisional","status":"derivado"}]} | ["La planta contiene una cota de losa distinta de la sección. Sección 7–7 adoptada: fondo −2,000 m, coronación de losa −1,000 m; apoyos acabados +0,500 m."] | {"Cota inferior relativa (m)":0.45,"Cota superior relativa (m)":0.5,"Cero absoluto de visualización (m)":286.1,"Estado del cero absoluto":"Provisional","Criterio":"Las cotas relativas proceden del dibujo; la equivalencia absoluta no está confirmada."} | F-SV1801B | ["SV1801B"] | [] | 7–7 | ["26E2/2589","26E2/2554","1FEB7"] | F-SV1801B/Cimentación del depósito SV1801B · mortero de apoyo 4 | {"boundingBoxM":{"min":[42.11411,29.895811,1.55],"max":[43.314621,31.07706,1.6]},"extentsM":[1.200511,1.181249,0.05],"meshSurfaceM2":1.610002,"meshVolumeM3":0.036,"closedSolid":true,"basis":"Magnitudes de las mallas representadas, no cantidades certificadas de obra, compra o fabricación. Las partes pueden compartir superficies; no se suman como un despiece de materiales."} | {"profileId":"grout_ha35","name":"Grout HA-35 sin retracción","materialName":"Mortero HA-35 de alta resistencia sin retracción","physicalMaterialStatus":"documentado","physicalMaterialSource":"Capa superior de 50 mm expresada en las secciones del fabricante","appearanceStatus":"criterio_visual","appearanceBasis":"Interpretación visual del material documental; el acabado, tono y parámetros PBR no son una especificación contractual.","note":"La apariencia gráfica no modifica ni confirma la especificación física del material."} | {"elementId":"found_0904_d2da6dd42bcec3","ifcGuid":"2SttgxIIvIzPOjGxSsJS6d","ifcClass":"IfcSlab","buildingId":"process_plant","buildingName":"Zona de separación de aire","sourceDocumentId":"LHD2609-JG00100-20260904","sourceRepresentationKind":"foundation"} | {"profileId":"grout_ha35","name":"Grout HA-35 sin retracción","status":"criterio_visual","basis":"Interpretación visual del material documental; el acabado, tono y parámetros PBR no son una especificación contractual.","physicalMaterialUnchanged":true} | SV1801B | 26E2/2589, 26E2/2554, 1FEB7 | Mortero HA-35 de alta resistencia sin retracción | 0.45 | 0.5 | 0.72 | 0.036 | Sección y contornos del fabricante; incidencias conservadas | Grout HA-35 sin retracción | found_0904_d2da6dd42bcec3 | documentado | Capa superior de 50 mm expresada en las secciones del fabricante | 1.20208 | 1.20208 | grout_ha35 | [0.792157,0.776471,0.721569] | 0.94 | La planta contiene una cota de losa distinta de la sección. Sección 7–7 adoptada: fondo −2,000 m, coronación de losa −1,000 m; apoyos acabados +0,500 m.
Base de autopresurización A · capa de limpieza | Hormigón de limpieza HA-20 | 2.61535 | 3.46983 | 0.1 | 285 | 285.1 | 15.16 | 0.704 | {"documentId":"LHD2609-JG00100-20260904","title":"Cimentaciones de equipos y pedestales del fabricante · revisión recibida 04/09/2026","date":"2026-09-04","sheet":"7.1–7.1","fileName":"LHD2609-JG00100_20260904.dwg","revisionCaveat":"Fecha de revisión tomada del nombre recibido; cajetines internos mantienen 02/07/2026 y algunos textos de plantilla.","sourceFileSha256":"b42eb027b7bc0b14c38d1d13514f4899b58a732aa8d0ba2ccf10fa2fc3192890"} | {"name":"Hormigón de limpieza HA-20","status":"documentado","source":"Secciones del fabricante: capa de limpieza de 100 mm; nota 2CED5"} | {"documented":[{"label":"Extensión local X","value":2.2,"unit":"m","source":"2593/2596, 2593/E28B, 1FECD","status":"derivada del contorno CAD"},{"label":"Extensión local Y","value":3.2,"unit":"m","source":"2593/2596, 2593/E28B, 1FECD","status":"derivada del contorno CAD"},{"label":"Cota inferior relativa adoptada","value":-1.1,"unit":"m","source":"7.1–7.1","status":"interpretación con conflicto conservado"},{"label":"Cota superior relativa adoptada","value":-1,"unit":"m","source":"7.1–7.1","status":"documentada / separación por material"}],"geometry":[{"label":"Extensión de la malla en X","value":2.6153499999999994,"unit":"m","source":"Geometría releída del IFC; datum absoluto de proceso provisional","status":"derivado"},{"label":"Extensión de la malla en Y","value":3.469827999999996,"unit":"m","source":"Geometría releída del IFC; datum absoluto de proceso provisional","status":"derivado"},{"label":"Extensión de la malla en Z","value":0.1,"unit":"m","source":"Geometría releída del IFC; datum absoluto de proceso provisional","status":"derivado"},{"label":"Cota inferior de visualización","value":285.0,"unit":"m","source":"Geometría releída del IFC; datum absoluto de proceso provisional","status":"derivado"},{"label":"Cota superior de visualización","value":285.1,"unit":"m","source":"Geometría releída del IFC; datum absoluto de proceso provisional","status":"derivado"}]} | ["El autopresurizador asociado al depósito no tiene objeto de equipo individual en el modelo; esta base no es el apoyo del tanque."] | {"Cota inferior relativa (m)":-1.1,"Cota superior relativa (m)":-1,"Cero absoluto de visualización (m)":286.1,"Estado del cero absoluto":"Provisional","Criterio":"Las cotas relativas proceden del dibujo; la equivalencia absoluta no está confirmada."} | F-AUTOPRES-A | [] | [] | 7.1–7.1 | ["2593/2596","2593/E28B","1FECD"] | F-AUTOPRES-A/Base de autopresurización A · capa de limpieza | {"boundingBoxM":{"min":[38.437624,30.316013,0.0],"max":[41.052974,33.785841,0.1]},"extentsM":[2.61535,3.469828,0.1],"meshSurfaceM2":15.16,"meshVolumeM3":0.704,"closedSolid":true,"basis":"Magnitudes de las mallas representadas, no cantidades certificadas de obra, compra o fabricación. Las partes pueden compartir superficies; no se suman como un despiece de materiales."} | {"profileId":"concrete_ha20","name":"Hormigón de limpieza HA-20","materialName":"Hormigón de limpieza HA-20","physicalMaterialStatus":"documentado","physicalMaterialSource":"Secciones del fabricante: capa de limpieza de 100 mm; nota 2CED5","appearanceStatus":"criterio_visual","appearanceBasis":"Interpretación visual del material documental; el acabado, tono y parámetros PBR no son una especificación contractual.","note":"La apariencia gráfica no modifica ni confirma la especificación física del material."} | {"elementId":"found_0904_5c71e991b6849e","ifcGuid":"3tZCJ4hNnUNg4lGZYHh0T8","ifcClass":"IfcSlab","buildingId":"process_plant","buildingName":"Zona de separación de aire","sourceDocumentId":"LHD2609-JG00100-20260904","sourceRepresentationKind":"foundation"} | {"profileId":"concrete_ha20","name":"Hormigón de limpieza HA-20","status":"criterio_visual","basis":"Interpretación visual del material documental; el acabado, tono y parámetros PBR no son una especificación contractual.","physicalMaterialUnchanged":true} |  | 2593/2596, 2593/E28B, 1FECD | Hormigón de limpieza HA-20 | -1.1 | -1 | 7.04 | 0.704 | Sección y contornos del fabricante; incidencias conservadas | Hormigón de limpieza HA-20 | found_0904_5c71e991b6849e | documentado | Secciones del fabricante: capa de limpieza de 100 mm; nota 2CED5 | 2.2 | 3.2 | concrete_ha20 | [0.721569,0.709804,0.658824] | 0.98 | El autopresurizador asociado al depósito no tiene objeto de equipo individual en el modelo; esta base no es el apoyo del tanque.
Base de autopresurización A · mortero superior de 50 mm | Mortero HA-35 de alta resistencia sin retracción | 2.38997 | 3.24445 | 0.05 | 286.25 | 286.3 | 12.5 | 0.3 | {"documentId":"LHD2609-JG00100-20260904","title":"Cimentaciones de equipos y pedestales del fabricante · revisión recibida 04/09/2026","date":"2026-09-04","sheet":"7.1–7.1","fileName":"LHD2609-JG00100_20260904.dwg","revisionCaveat":"Fecha de revisión tomada del nombre recibido; cajetines internos mantienen 02/07/2026 y algunos textos de plantilla.","sourceFileSha256":"b42eb027b7bc0b14c38d1d13514f4899b58a732aa8d0ba2ccf10fa2fc3192890"} | {"name":"Mortero HA-35 de alta resistencia sin retracción","status":"documentado","source":"Capa superior de 50 mm expresada en las secciones del fabricante"} | {"documented":[{"label":"Extensión local X","value":2.0,"unit":"m","source":"2593/2596, 2593/E28B, 1FECD","status":"derivada del contorno CAD"},{"label":"Extensión local Y","value":3.0,"unit":"m","source":"2593/2596, 2593/E28B, 1FECD","status":"derivada del contorno CAD"},{"label":"Cota inferior relativa adoptada","value":0.15000000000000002,"unit":"m","source":"7.1–7.1","status":"interpretación con conflicto conservado"},{"label":"Cota superior relativa adoptada","value":0.2,"unit":"m","source":"7.1–7.1","status":"documentada / separación por material"}],"geometry":[{"label":"Extensión de la malla en X","value":2.3899740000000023,"unit":"m","source":"Geometría releída del IFC; datum absoluto de proceso provisional","status":"derivado"},{"label":"Extensión de la malla en Y","value":3.2444500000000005,"unit":"m","source":"Geometría releída del IFC; datum absoluto de proceso provisional","status":"derivado"},{"label":"Extensión de la malla en Z","value":0.050000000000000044,"unit":"m","source":"Geometría releída del IFC; datum absoluto de proceso provisional","status":"derivado"},{"label":"Cota inferior de visualización","value":286.25,"unit":"m","source":"Geometría releída del IFC; datum absoluto de proceso provisional","status":"derivado"},{"label":"Cota superior de visualización","value":286.3,"unit":"m","source":"Geometría releída del IFC; datum absoluto de proceso provisional","status":"derivado"}]} | ["El autopresurizador asociado al depósito no tiene objeto de equipo individual en el modelo; esta base no es el apoyo del tanque."] | {"Cota inferior relativa (m)":0.15000000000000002,"Cota superior relativa (m)":0.2,"Cero absoluto de visualización (m)":286.1,"Estado del cero absoluto":"Provisional","Criterio":"Las cotas relativas proceden del dibujo; la equivalencia absoluta no está confirmada."} | F-AUTOPRES-A | [] | [] | 7.1–7.1 | ["2593/2596","2593/E28B","1FECD"] | F-AUTOPRES-A/Base de autopresurización A · mortero superior de 50 mm | {"boundingBoxM":{"min":[38.550312,30.428702,1.25],"max":[40.940286,33.673152,1.3]},"extentsM":[2.389974,3.24445,0.05],"meshSurfaceM2":12.500001,"meshVolumeM3":0.3,"closedSolid":true,"basis":"Magnitudes de las mallas representadas, no cantidades certificadas de obra, compra o fabricación. Las partes pueden compartir superficies; no se suman como un despiece de materiales."} | {"profileId":"grout_ha35","name":"Grout HA-35 sin retracción","materialName":"Mortero HA-35 de alta resistencia sin retracción","physicalMaterialStatus":"documentado","physicalMaterialSource":"Capa superior de 50 mm expresada en las secciones del fabricante","appearanceStatus":"criterio_visual","appearanceBasis":"Interpretación visual del material documental; el acabado, tono y parámetros PBR no son una especificación contractual.","note":"La apariencia gráfica no modifica ni confirma la especificación física del material."} | {"elementId":"found_0904_3d5084fedbdd68","ifcGuid":"2rf5wn7FzIMOcN6D7fSKuQ","ifcClass":"IfcSlab","buildingId":"process_plant","buildingName":"Zona de separación de aire","sourceDocumentId":"LHD2609-JG00100-20260904","sourceRepresentationKind":"foundation"} | {"profileId":"grout_ha35","name":"Grout HA-35 sin retracción","status":"criterio_visual","basis":"Interpretación visual del material documental; el acabado, tono y parámetros PBR no son una especificación contractual.","physicalMaterialUnchanged":true} |  | 2593/2596, 2593/E28B, 1FECD | Mortero HA-35 de alta resistencia sin retracción | 0.15 | 0.2 | 6 | 0.3 | Sección y contornos del fabricante; incidencias conservadas | Grout HA-35 sin retracción | found_0904_3d5084fedbdd68 | documentado | Capa superior de 50 mm expresada en las secciones del fabricante | 2 | 3 | grout_ha35 | [0.792157,0.776471,0.721569] | 0.94 | El autopresurizador asociado al depósito no tiene objeto de equipo individual en el modelo; esta base no es el apoyo del tanque.
Base de autopresurización B · capa de limpieza | Hormigón de limpieza HA-20 | 2.61535 | 3.46983 | 0.1 | 285 | 285.1 | 15.16 | 0.704 | {"documentId":"LHD2609-JG00100-20260904","title":"Cimentaciones de equipos y pedestales del fabricante · revisión recibida 04/09/2026","date":"2026-09-04","sheet":"7.1–7.1","fileName":"LHD2609-JG00100_20260904.dwg","revisionCaveat":"Fecha de revisión tomada del nombre recibido; cajetines internos mantienen 02/07/2026 y algunos textos de plantilla.","sourceFileSha256":"b42eb027b7bc0b14c38d1d13514f4899b58a732aa8d0ba2ccf10fa2fc3192890"} | {"name":"Hormigón de limpieza HA-20","status":"documentado","source":"Secciones del fabricante: capa de limpieza de 100 mm; nota 2CED5"} | {"documented":[{"label":"Extensión local X","value":2.2,"unit":"m","source":"26E3/2596, 26E3/E28B, 1FECD","status":"derivada del contorno CAD"},{"label":"Extensión local Y","value":3.2,"unit":"m","source":"26E3/2596, 26E3/E28B, 1FECD","status":"derivada del contorno CAD"},{"label":"Cota inferior relativa adoptada","value":-1.1,"unit":"m","source":"7.1–7.1","status":"interpretación con conflicto conservado"},{"label":"Cota superior relativa adoptada","value":-1,"unit":"m","source":"7.1–7.1","status":"documentada / separación por material"}],"geometry":[{"label":"Extensión de la malla en X","value":2.6153499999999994,"unit":"m","source":"Geometría releída del IFC; datum absoluto de proceso provisional","status":"derivado"},{"label":"Extensión de la malla en Y","value":3.469827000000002,"unit":"m","source":"Geometría releída del IFC; datum absoluto de proceso provisional","status":"derivado"},{"label":"Extensión de la malla en Z","value":0.1,"unit":"m","source":"Geometría releída del IFC; datum absoluto de proceso provisional","status":"derivado"},{"label":"Cota inferior de visualización","value":285.0,"unit":"m","source":"Geometría releída del IFC; datum absoluto de proceso provisional","status":"derivado"},{"label":"Cota superior de visualización","value":285.1,"unit":"m","source":"Geometría releída del IFC; datum absoluto de proceso provisional","status":"derivado"}]} | ["El autopresurizador asociado al depósito no tiene objeto de equipo individual en el modelo; esta base no es el apoyo del tanque."] | {"Cota inferior relativa (m)":-1.1,"Cota superior relativa (m)":-1,"Cero absoluto de visualización (m)":286.1,"Estado del cero absoluto":"Provisional","Criterio":"Las cotas relativas proceden del dibujo; la equivalencia absoluta no está confirmada."} | F-AUTOPRES-B | [] | [] | 7.1–7.1 | ["26E3/2596","26E3/E28B","1FECD"] | F-AUTOPRES-B/Base de autopresurización B · capa de limpieza | {"boundingBoxM":{"min":[46.065866,29.267243,0.0],"max":[48.681216,32.73707,0.1]},"extentsM":[2.61535,3.469827,0.1],"meshSurfaceM2":15.159997,"meshVolumeM3":0.704,"closedSolid":true,"basis":"Magnitudes de las mallas representadas, no cantidades certificadas de obra, compra o fabricación. Las partes pueden compartir superficies; no se suman como un despiece de materiales."} | {"profileId":"concrete_ha20","name":"Hormigón de limpieza HA-20","materialName":"Hormigón de limpieza HA-20","physicalMaterialStatus":"documentado","physicalMaterialSource":"Secciones del fabricante: capa de limpieza de 100 mm; nota 2CED5","appearanceStatus":"criterio_visual","appearanceBasis":"Interpretación visual del material documental; el acabado, tono y parámetros PBR no son una especificación contractual.","note":"La apariencia gráfica no modifica ni confirma la especificación física del material."} | {"elementId":"found_0904_af64e6d0788490","ifcGuid":"3fQPIITmDUn9bjbSNN663v","ifcClass":"IfcSlab","buildingId":"process_plant","buildingName":"Zona de separación de aire","sourceDocumentId":"LHD2609-JG00100-20260904","sourceRepresentationKind":"foundation"} | {"profileId":"concrete_ha20","name":"Hormigón de limpieza HA-20","status":"criterio_visual","basis":"Interpretación visual del material documental; el acabado, tono y parámetros PBR no son una especificación contractual.","physicalMaterialUnchanged":true} |  | 26E3/2596, 26E3/E28B, 1FECD | Hormigón de limpieza HA-20 | -1.1 | -1 | 7.04 | 0.704 | Sección y contornos del fabricante; incidencias conservadas | Hormigón de limpieza HA-20 | found_0904_af64e6d0788490 | documentado | Secciones del fabricante: capa de limpieza de 100 mm; nota 2CED5 | 2.2 | 3.2 | concrete_ha20 | [0.721569,0.709804,0.658824] | 0.98 | El autopresurizador asociado al depósito no tiene objeto de equipo individual en el modelo; esta base no es el apoyo del tanque.
Base de autopresurización B · mortero superior de 50 mm | Mortero HA-35 de alta resistencia sin retracción | 2.38997 | 3.24445 | 0.05 | 286.25 | 286.3 | 12.5 | 0.3 | {"documentId":"LHD2609-JG00100-20260904","title":"Cimentaciones de equipos y pedestales del fabricante · revisión recibida 04/09/2026","date":"2026-09-04","sheet":"7.1–7.1","fileName":"LHD2609-JG00100_20260904.dwg","revisionCaveat":"Fecha de revisión tomada del nombre recibido; cajetines internos mantienen 02/07/2026 y algunos textos de plantilla.","sourceFileSha256":"b42eb027b7bc0b14c38d1d13514f4899b58a732aa8d0ba2ccf10fa2fc3192890"} | {"name":"Mortero HA-35 de alta resistencia sin retracción","status":"documentado","source":"Capa superior de 50 mm expresada en las secciones del fabricante"} | {"documented":[{"label":"Extensión local X","value":2.0,"unit":"m","source":"26E3/2596, 26E3/E28B, 1FECD","status":"derivada del contorno CAD"},{"label":"Extensión local Y","value":3.0,"unit":"m","source":"26E3/2596, 26E3/E28B, 1FECD","status":"derivada del contorno CAD"},{"label":"Cota inferior relativa adoptada","value":0.15000000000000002,"unit":"m","source":"7.1–7.1","status":"interpretación con conflicto conservado"},{"label":"Cota superior relativa adoptada","value":0.2,"unit":"m","source":"7.1–7.1","status":"documentada / separación por material"}],"geometry":[{"label":"Extensión de la malla en X","value":2.3899740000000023,"unit":"m","source":"Geometría releída del IFC; datum absoluto de proceso provisional","status":"derivado"},{"label":"Extensión de la malla en Y","value":3.244449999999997,"unit":"m","source":"Geometría releída del IFC; datum absoluto de proceso provisional","status":"derivado"},{"label":"Extensión de la malla en Z","value":0.050000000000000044,"unit":"m","source":"Geometría releída del IFC; datum absoluto de proceso provisional","status":"derivado"},{"label":"Cota inferior de visualización","value":286.25,"unit":"m","source":"Geometría releída del IFC; datum absoluto de proceso provisional","status":"derivado"},{"label":"Cota superior de visualización","value":286.3,"unit":"m","source":"Geometría releída del IFC; datum absoluto de proceso provisional","status":"derivado"}]} | ["El autopresurizador asociado al depósito no tiene objeto de equipo individual en el modelo; esta base no es el apoyo del tanque."] | {"Cota inferior relativa (m)":0.15000000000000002,"Cota superior relativa (m)":0.2,"Cero absoluto de visualización (m)":286.1,"Estado del cero absoluto":"Provisional","Criterio":"Las cotas relativas proceden del dibujo; la equivalencia absoluta no está confirmada."} | F-AUTOPRES-B | [] | [] | 7.1–7.1 | ["26E3/2596","26E3/E28B","1FECD"] | F-AUTOPRES-B/Base de autopresurización B · mortero superior de 50 mm | {"boundingBoxM":{"min":[46.178554,29.379932,1.25],"max":[48.568528,32.624382,1.3]},"extentsM":[2.389974,3.24445,0.05],"meshSurfaceM2":12.500002,"meshVolumeM3":0.3,"closedSolid":true,"basis":"Magnitudes de las mallas representadas, no cantidades certificadas de obra, compra o fabricación. Las partes pueden compartir superficies; no se suman como un despiece de materiales."} | {"profileId":"grout_ha35","name":"Grout HA-35 sin retracción","materialName":"Mortero HA-35 de alta resistencia sin retracción","physicalMaterialStatus":"documentado","physicalMaterialSource":"Capa superior de 50 mm expresada en las secciones del fabricante","appearanceStatus":"criterio_visual","appearanceBasis":"Interpretación visual del material documental; el acabado, tono y parámetros PBR no son una especificación contractual.","note":"La apariencia gráfica no modifica ni confirma la especificación física del material."} | {"elementId":"found_0904_b788ec56b7faec","ifcGuid":"0DU4BnUnHLOOoMYaplgqAh","ifcClass":"IfcSlab","buildingId":"process_plant","buildingName":"Zona de separación de aire","sourceDocumentId":"LHD2609-JG00100-20260904","sourceRepresentationKind":"foundation"} | {"profileId":"grout_ha35","name":"Grout HA-35 sin retracción","status":"criterio_visual","basis":"Interpretación visual del material documental; el acabado, tono y parámetros PBR no son una especificación contractual.","physicalMaterialUnchanged":true} |  | 26E3/2596, 26E3/E28B, 1FECD | Mortero HA-35 de alta resistencia sin retracción | 0.15 | 0.2 | 6 | 0.3 | Sección y contornos del fabricante; incidencias conservadas | Grout HA-35 sin retracción | found_0904_b788ec56b7faec | documentado | Capa superior de 50 mm expresada en las secciones del fabricante | 2 | 3 | grout_ha35 | [0.792157,0.776471,0.721569] | 0.94 | El autopresurizador asociado al depósito no tiene objeto de equipo individual en el modelo; esta base no es el apoyo del tanque.
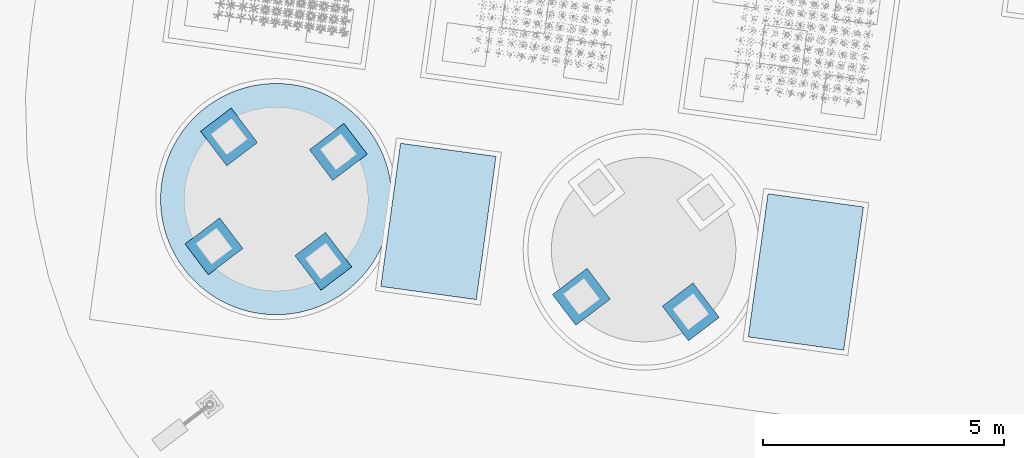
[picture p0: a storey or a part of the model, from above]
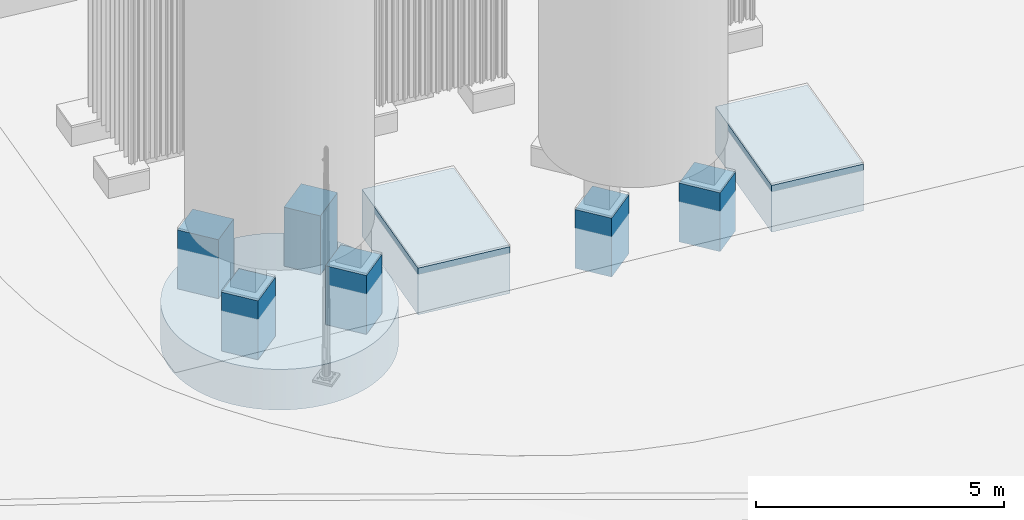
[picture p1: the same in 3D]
Properties of the parts of a building model (IFC4), part 105 of 134

# IfcSlab: Cimentación industrial (108)
Name | Material | Extensión de la malla en X (m) = ExtensionX (m) | Extensión de la malla en Y (m) = ExtensionY (m) | Extensión de la malla en Z (m) = ExtensionZ (m) = Espesor o altura real de sección (m) | Cota inferior de visualización (m) | Cota superior de visualización (m) | SuperficieDeLaMalla (m2) | VolumenGeometrico (m3) | JH_InformacionBIM, source = DocumentoFuente | material | dimensions | issues = IncidenciasPendientes | positioning = PosicionYEstado | assemblyId = Conjunto de cimentación | equipmentIds | supportPositionIds | sectionRef = Sección de referencia | sourceCadHandles | stableElementKey | geometryMetrics | materialAppearance | visualizationIdentity | appearance | Equipos asociados | Identificadores CAD de referencia | JH_Trazabilidad, Material = name | Cota inferior relativa (m) = Cota inferior relativa adoptada (m) | Cota superior relativa (m) = Cota superior relativa adoptada (m) | Área de planta (m²) | Volumen geométrico (m³) | Estado de la geometría | Acabado de visualización = Acabado | Identificador | status | JH_EvidenciaDeMaterial, source | Extensión local X (m) | Extensión local Y (m) | Perfil | ColorRGB | Rugosidad | Incidencias de origen
Cimentación del vaporizador LV1802A · capa de limpieza | Hormigón de limpieza HA-20 | 4.6853 | 4.11793 | 0.1 | 284 | 284.1 | 31.8556 | 1.51466 | {"documentId":"LHD2609-JG00100-20260904","title":"Cimentaciones de equipos y pedestales del fabricante · revisión recibida 04/09/2026","date":"2026-09-04","sheet":"8–8","fileName":"LHD2609-JG00100_20260904.dwg","revisionCaveat":"Fecha de revisión tomada del nombre recibido; cajetines internos mantienen 02/07/2026 y algunos textos de plantilla.","sourceFileSha256":"b42eb027b7bc0b14c38d1d13514f4899b58a732aa8d0ba2ccf10fa2fc3192890"} | {"name":"Hormigón de limpieza HA-20","status":"documentado","source":"Secciones del fabricante: capa de limpieza de 100 mm; nota 2CED5"} | {"documented":[{"label":"Extensión local X","value":4.238,"unit":"m","source":"25A3/25CB, 25A3/E3A8, 1FEC2","status":"derivada del contorno CAD"},{"label":"Extensión local Y","value":3.574,"unit":"m","source":"25A3/25CB, 25A3/E3A8, 1FEC2","status":"derivada del contorno CAD"},{"label":"Cota inferior relativa adoptada","value":-2.1,"unit":"m","source":"8–8","status":"interpretación con conflicto conservado"},{"label":"Cota superior relativa adoptada","value":-2,"unit":"m","source":"8–8","status":"documentada / separación por material"}],"geometry":[{"label":"Extensión de la malla en X","value":4.685297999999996,"unit":"m","source":"Geometría releída del IFC; datum absoluto de proceso provisional","status":"derivado"},{"label":"Extensión de la malla en Y","value":4.117926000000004,"unit":"m","source":"Geometría releída del IFC; datum absoluto de proceso provisional","status":"derivado"},{"label":"Extensión de la malla en Z","value":0.09999999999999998,"unit":"m","source":"Geometría releída del IFC; datum absoluto de proceso provisional","status":"derivado"},{"label":"Cota inferior de visualización","value":284.0,"unit":"m","source":"Geometría releída del IFC; datum absoluto de proceso provisional","status":"derivado"},{"label":"Cota superior de visualización","value":284.1,"unit":"m","source":"Geometría releída del IFC; datum absoluto de proceso provisional","status":"derivado"}]} | ["Planta: −2,400 m. Sección 8–8: fondo −2,000 m, coronación de losa −1,400 m. Se adopta sección; pendiente de aclaración."] | {"Cota inferior relativa (m)":-2.1,"Cota superior relativa (m)":-2,"Cero absoluto de visualización (m)":286.1,"Estado del cero absoluto":"Provisional","Criterio":"Las cotas relativas proceden del dibujo; la equivalencia absoluta no está confirmada."} | F-LV1802A | ["LV1802A"] | [] | 8–8 | ["25A3/25CB","25A3/E3A8","1FEC2"] | F-LV1802A/Cimentación del vaporizador LV1802A · capa de limpieza | {"boundingBoxM":{"min":[34.021771,35.202006,-1.0],"max":[38.707069,39.319932,-0.9]},"extentsM":[4.685298,4.117926,0.1],"meshSurfaceM2":31.855624,"meshVolumeM3":1.514661,"closedSolid":true,"basis":"Magnitudes de las mallas representadas, no cantidades certificadas de obra, compra o fabricación. Las partes pueden compartir superficies; no se suman como un despiece de materiales."} | {"profileId":"concrete_ha20","name":"Hormigón de limpieza HA-20","materialName":"Hormigón de limpieza HA-20","physicalMaterialStatus":"documentado","physicalMaterialSource":"Secciones del fabricante: capa de limpieza de 100 mm; nota 2CED5","appearanceStatus":"criterio_visual","appearanceBasis":"Interpretación visual del material documental; el acabado, tono y parámetros PBR no son una especificación contractual.","note":"La apariencia gráfica no modifica ni confirma la especificación física del material."} | {"elementId":"found_0904_c812033c264f6a","ifcGuid":"2G5ahN0TLIbhP7ehucO0ih","ifcClass":"IfcSlab","buildingId":"process_plant","buildingName":"Zona de separación de aire","sourceDocumentId":"LHD2609-JG00100-20260904","sourceRepresentationKind":"foundation"} | {"profileId":"concrete_ha20","name":"Hormigón de limpieza HA-20","status":"criterio_visual","basis":"Interpretación visual del material documental; el acabado, tono y parámetros PBR no son una especificación contractual.","physicalMaterialUnchanged":true} | LV1802A | 25A3/25CB, 25A3/E3A8, 1FEC2 | Hormigón de limpieza HA-20 | -2.1 | -2 | 15.1466 | 1.51466 | Sección y contornos del fabricante; incidencias conservadas | Hormigón de limpieza HA-20 | found_0904_c812033c264f6a | documentado | Secciones del fabricante: capa de limpieza de 100 mm; nota 2CED5 | 4.238 | 3.574 | concrete_ha20 | [0.721569,0.709804,0.658824] | 0.98 | Planta: −2,400 m. Sección 8–8: fondo −2,000 m, coronación de losa −1,400 m. Se adopta sección; pendiente de aclaración.
Cimentación del vaporizador LV1802A · mortero de apoyo 1 | Mortero HA-35 de alta resistencia sin retracción | 1.00058 | 0.915128 | 0.05 | 286.565 | 286.615 | 1.61 | 0.036 | {"documentId":"LHD2609-JG00100-20260904","title":"Cimentaciones de equipos y pedestales del fabricante · revisión recibida 04/09/2026","date":"2026-09-04","sheet":"8–8","fileName":"LHD2609-JG00100_20260904.dwg","revisionCaveat":"Fecha de revisión tomada del nombre recibido; cajetines internos mantienen 02/07/2026 y algunos textos de plantilla.","sourceFileSha256":"b42eb027b7bc0b14c38d1d13514f4899b58a732aa8d0ba2ccf10fa2fc3192890"} | {"name":"Mortero HA-35 de alta resistencia sin retracción","status":"documentado","source":"Capa superior de 50 mm expresada en las secciones del fabricante"} | {"documented":[{"label":"Extensión local X","value":0.9,"unit":"m","source":"25A3/25CB, 25A3/E3A8, 1FEC2","status":"derivada del contorno CAD"},{"label":"Extensión local Y","value":0.8,"unit":"m","source":"25A3/25CB, 25A3/E3A8, 1FEC2","status":"derivada del contorno CAD"},{"label":"Cota inferior relativa adoptada","value":0.465,"unit":"m","source":"8–8","status":"interpretación con conflicto conservado"},{"label":"Cota superior relativa adoptada","value":0.515,"unit":"m","source":"8–8","status":"documentada / separación por material"}],"geometry":[{"label":"Extensión de la malla en X","value":1.0005760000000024,"unit":"m","source":"Geometría releída del IFC; datum absoluto de proceso provisional","status":"derivado"},{"label":"Extensión de la malla en Y","value":0.9151279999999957,"unit":"m","source":"Geometría releída del IFC; datum absoluto de proceso provisional","status":"derivado"},{"label":"Extensión de la malla en Z","value":0.050000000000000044,"unit":"m","source":"Geometría releída del IFC; datum absoluto de proceso provisional","status":"derivado"},{"label":"Cota inferior de visualización","value":286.565,"unit":"m","source":"Geometría releída del IFC; datum absoluto de proceso provisional","status":"derivado"},{"label":"Cota superior de visualización","value":286.615,"unit":"m","source":"Geometría releída del IFC; datum absoluto de proceso provisional","status":"derivado"}]} | ["Planta: −2,400 m. Sección 8–8: fondo −2,000 m, coronación de losa −1,400 m. Se adopta sección; pendiente de aclaración."] | {"Cota inferior relativa (m)":0.465,"Cota superior relativa (m)":0.515,"Cero absoluto de visualización (m)":286.1,"Estado del cero absoluto":"Provisional","Criterio":"Las cotas relativas proceden del dibujo; la equivalencia absoluta no está confirmada."} | F-LV1802A | ["LV1802A"] | [] | 8–8 | ["25A3/25CB","25A3/E3A8","1FEC2"] | F-LV1802A/Cimentación del vaporizador LV1802A · mortero de apoyo 1 | {"boundingBoxM":{"min":[34.741391,37.95405,1.565],"max":[35.741967,38.869178,1.615]},"extentsM":[1.000576,0.915128,0.05],"meshSurfaceM2":1.61,"meshVolumeM3":0.036,"closedSolid":true,"basis":"Magnitudes de las mallas representadas, no cantidades certificadas de obra, compra o fabricación. Las partes pueden compartir superficies; no se suman como un despiece de materiales."} | {"profileId":"grout_ha35","name":"Grout HA-35 sin retracción","materialName":"Mortero HA-35 de alta resistencia sin retracción","physicalMaterialStatus":"documentado","physicalMaterialSource":"Capa superior de 50 mm expresada en las secciones del fabricante","appearanceStatus":"criterio_visual","appearanceBasis":"Interpretación visual del material documental; el acabado, tono y parámetros PBR no son una especificación contractual.","note":"La apariencia gráfica no modifica ni confirma la especificación física del material."} | {"elementId":"found_0904_000439dfe0661c","ifcGuid":"2Sz6WdkuvOqRS5wElLEDsS","ifcClass":"IfcSlab","buildingId":"process_plant","buildingName":"Zona de separación de aire","sourceDocumentId":"LHD2609-JG00100-20260904","sourceRepresentationKind":"foundation"} | {"profileId":"grout_ha35","name":"Grout HA-35 sin retracción","status":"criterio_visual","basis":"Interpretación visual del material documental; el acabado, tono y parámetros PBR no son una especificación contractual.","physicalMaterialUnchanged":true} | LV1802A | 25A3/25CB, 25A3/E3A8, 1FEC2 | Mortero HA-35 de alta resistencia sin retracción | 0.465 | 0.515 | 0.72 | 0.036 | Sección y contornos del fabricante; incidencias conservadas | Grout HA-35 sin retracción | found_0904_000439dfe0661c | documentado | Capa superior de 50 mm expresada en las secciones del fabricante | 0.9 | 0.8 | grout_ha35 | [0.792157,0.776471,0.721569] | 0.94 | Planta: −2,400 m. Sección 8–8: fondo −2,000 m, coronación de losa −1,400 m. Se adopta sección; pendiente de aclaración.
Cimentación del vaporizador LV1802A · mortero de apoyo 2 | Mortero HA-35 de alta resistencia sin retracción | 1.00058 | 0.915128 | 0.05 | 286.565 | 286.615 | 1.61 | 0.036 | {"documentId":"LHD2609-JG00100-20260904","title":"Cimentaciones de equipos y pedestales del fabricante · revisión recibida 04/09/2026","date":"2026-09-04","sheet":"8–8","fileName":"LHD2609-JG00100_20260904.dwg","revisionCaveat":"Fecha de revisión tomada del nombre recibido; cajetines internos mantienen 02/07/2026 y algunos textos de plantilla.","sourceFileSha256":"b42eb027b7bc0b14c38d1d13514f4899b58a732aa8d0ba2ccf10fa2fc3192890"} | {"name":"Mortero HA-35 de alta resistencia sin retracción","status":"documentado","source":"Capa superior de 50 mm expresada en las secciones del fabricante"} | {"documented":[{"label":"Extensión local X","value":0.9,"unit":"m","source":"25A3/25CB, 25A3/E3A8, 1FEC2","status":"derivada del contorno CAD"},{"label":"Extensión local Y","value":0.8,"unit":"m","source":"25A3/25CB, 25A3/E3A8, 1FEC2","status":"derivada del contorno CAD"},{"label":"Cota inferior relativa adoptada","value":0.465,"unit":"m","source":"8–8","status":"interpretación con conflicto conservado"},{"label":"Cota superior relativa adoptada","value":0.515,"unit":"m","source":"8–8","status":"documentada / separación por material"}],"geometry":[{"label":"Extensión de la malla en X","value":1.0005760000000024,"unit":"m","source":"Geometría releída del IFC; datum absoluto de proceso provisional","status":"derivado"},{"label":"Extensión de la malla en Y","value":0.9151279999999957,"unit":"m","source":"Geometría releída del IFC; datum absoluto de proceso provisional","status":"derivado"},{"label":"Extensión de la malla en Z","value":0.050000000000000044,"unit":"m","source":"Geometría releída del IFC; datum absoluto de proceso provisional","status":"derivado"},{"label":"Cota inferior de visualización","value":286.565,"unit":"m","source":"Geometría releída del IFC; datum absoluto de proceso provisional","status":"derivado"},{"label":"Cota superior de visualización","value":286.615,"unit":"m","source":"Geometría releída del IFC; datum absoluto de proceso provisional","status":"derivado"}]} | ["Planta: −2,400 m. Sección 8–8: fondo −2,000 m, coronación de losa −1,400 m. Se adopta sección; pendiente de aclaración."] | {"Cota inferior relativa (m)":0.465,"Cota superior relativa (m)":0.515,"Cero absoluto de visualización (m)":286.1,"Estado del cero absoluto":"Provisional","Criterio":"Las cotas relativas proceden del dibujo; la equivalencia absoluta no está confirmada."} | F-LV1802A | ["LV1802A"] | [] | 8–8 | ["25A3/25CB","25A3/E3A8","1FEC2"] | F-LV1802A/Cimentación del vaporizador LV1802A · mortero de apoyo 2 | {"boundingBoxM":{"min":[37.255739,37.608364,1.565],"max":[38.256315,38.523492,1.615]},"extentsM":[1.000576,0.915128,0.05],"meshSurfaceM2":1.61,"meshVolumeM3":0.036,"closedSolid":true,"basis":"Magnitudes de las mallas representadas, no cantidades certificadas de obra, compra o fabricación. Las partes pueden compartir superficies; no se suman como un despiece de materiales."} | {"profileId":"grout_ha35","name":"Grout HA-35 sin retracción","materialName":"Mortero HA-35 de alta resistencia sin retracción","physicalMaterialStatus":"documentado","physicalMaterialSource":"Capa superior de 50 mm expresada en las secciones del fabricante","appearanceStatus":"criterio_visual","appearanceBasis":"Interpretación visual del material documental; el acabado, tono y parámetros PBR no son una especificación contractual.","note":"La apariencia gráfica no modifica ni confirma la especificación física del material."} | {"elementId":"found_0904_d2eeef9f2cad66","ifcGuid":"3ZJzACGvnIHPjG2FmMLy6A","ifcClass":"IfcSlab","buildingId":"process_plant","buildingName":"Zona de separación de aire","sourceDocumentId":"LHD2609-JG00100-20260904","sourceRepresentationKind":"foundation"} | {"profileId":"grout_ha35","name":"Grout HA-35 sin retracción","status":"criterio_visual","basis":"Interpretación visual del material documental; el acabado, tono y parámetros PBR no son una especificación contractual.","physicalMaterialUnchanged":true} | LV1802A | 25A3/25CB, 25A3/E3A8, 1FEC2 | Mortero HA-35 de alta resistencia sin retracción | 0.465 | 0.515 | 0.72 | 0.036 | Sección y contornos del fabricante; incidencias conservadas | Grout HA-35 sin retracción | found_0904_d2eeef9f2cad66 | documentado | Capa superior de 50 mm expresada en las secciones del fabricante | 0.9 | 0.8 | grout_ha35 | [0.792157,0.776471,0.721569] | 0.94 | Planta: −2,400 m. Sección 8–8: fondo −2,000 m, coronación de losa −1,400 m. Se adopta sección; pendiente de aclaración.
Cimentación del vaporizador LV1802A · mortero de apoyo 3 | Mortero HA-35 de alta resistencia sin retracción | 1.00058 | 0.915129 | 0.05 | 286.565 | 286.615 | 1.61 | 0.036 | {"documentId":"LHD2609-JG00100-20260904","title":"Cimentaciones de equipos y pedestales del fabricante · revisión recibida 04/09/2026","date":"2026-09-04","sheet":"8–8","fileName":"LHD2609-JG00100_20260904.dwg","revisionCaveat":"Fecha de revisión tomada del nombre recibido; cajetines internos mantienen 02/07/2026 y algunos textos de plantilla.","sourceFileSha256":"b42eb027b7bc0b14c38d1d13514f4899b58a732aa8d0ba2ccf10fa2fc3192890"} | {"name":"Mortero HA-35 de alta resistencia sin retracción","status":"documentado","source":"Capa superior de 50 mm expresada en las secciones del fabricante"} | {"documented":[{"label":"Extensión local X","value":0.9,"unit":"m","source":"25A3/25CB, 25A3/E3A8, 1FEC2","status":"derivada del contorno CAD"},{"label":"Extensión local Y","value":0.8,"unit":"m","source":"25A3/25CB, 25A3/E3A8, 1FEC2","status":"derivada del contorno CAD"},{"label":"Cota inferior relativa adoptada","value":0.465,"unit":"m","source":"8–8","status":"interpretación con conflicto conservado"},{"label":"Cota superior relativa adoptada","value":0.515,"unit":"m","source":"8–8","status":"documentada / separación por material"}],"geometry":[{"label":"Extensión de la malla en X","value":1.0005759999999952,"unit":"m","source":"Geometría releída del IFC; datum absoluto de proceso provisional","status":"derivado"},{"label":"Extensión de la malla en Y","value":0.9151290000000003,"unit":"m","source":"Geometría releída del IFC; datum absoluto de proceso provisional","status":"derivado"},{"label":"Extensión de la malla en Z","value":0.050000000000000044,"unit":"m","source":"Geometría releída del IFC; datum absoluto de proceso provisional","status":"derivado"},{"label":"Cota inferior de visualización","value":286.565,"unit":"m","source":"Geometría releída del IFC; datum absoluto de proceso provisional","status":"derivado"},{"label":"Cota superior de visualización","value":286.615,"unit":"m","source":"Geometría releída del IFC; datum absoluto de proceso provisional","status":"derivado"}]} | ["Planta: −2,400 m. Sección 8–8: fondo −2,000 m, coronación de losa −1,400 m. Se adopta sección; pendiente de aclaración."] | {"Cota inferior relativa (m)":0.465,"Cota superior relativa (m)":0.515,"Cero absoluto de visualización (m)":286.1,"Estado del cero absoluto":"Provisional","Criterio":"Las cotas relativas proceden del dibujo; la equivalencia absoluta no está confirmada."} | F-LV1802A | ["LV1802A"] | [] | 8–8 | ["25A3/25CB","25A3/E3A8","1FEC2"] | F-LV1802A/Cimentación del vaporizador LV1802A · mortero de apoyo 3 | {"boundingBoxM":{"min":[36.986873,35.65276,1.565],"max":[37.987449,36.567889,1.615]},"extentsM":[1.000576,0.915129,0.05],"meshSurfaceM2":1.610001,"meshVolumeM3":0.036,"closedSolid":true,"basis":"Magnitudes de las mallas representadas, no cantidades certificadas de obra, compra o fabricación. Las partes pueden compartir superficies; no se suman como un despiece de materiales."} | {"profileId":"grout_ha35","name":"Grout HA-35 sin retracción","materialName":"Mortero HA-35 de alta resistencia sin retracción","physicalMaterialStatus":"documentado","physicalMaterialSource":"Capa superior de 50 mm expresada en las secciones del fabricante","appearanceStatus":"criterio_visual","appearanceBasis":"Interpretación visual del material documental; el acabado, tono y parámetros PBR no son una especificación contractual.","note":"La apariencia gráfica no modifica ni confirma la especificación física del material."} | {"elementId":"found_0904_904f51f45370d0","ifcGuid":"1jV_2UwmHVHxgRSHqXxwTq","ifcClass":"IfcSlab","buildingId":"process_plant","buildingName":"Zona de separación de aire","sourceDocumentId":"LHD2609-JG00100-20260904","sourceRepresentationKind":"foundation"} | {"profileId":"grout_ha35","name":"Grout HA-35 sin retracción","status":"criterio_visual","basis":"Interpretación visual del material documental; el acabado, tono y parámetros PBR no son una especificación contractual.","physicalMaterialUnchanged":true} | LV1802A | 25A3/25CB, 25A3/E3A8, 1FEC2 | Mortero HA-35 de alta resistencia sin retracción | 0.465 | 0.515 | 0.72 | 0.036 | Sección y contornos del fabricante; incidencias conservadas | Grout HA-35 sin retracción | found_0904_904f51f45370d0 | documentado | Capa superior de 50 mm expresada en las secciones del fabricante | 0.9 | 0.8 | grout_ha35 | [0.792157,0.776471,0.721569] | 0.94 | Planta: −2,400 m. Sección 8–8: fondo −2,000 m, coronación de losa −1,400 m. Se adopta sección; pendiente de aclaración.
Cimentación del vaporizador LV1802A · mortero de apoyo 4 | Mortero HA-35 de alta resistencia sin retracción | 1.00058 | 0.915128 | 0.05 | 286.565 | 286.615 | 1.61 | 0.036 | {"documentId":"LHD2609-JG00100-20260904","title":"Cimentaciones de equipos y pedestales del fabricante · revisión recibida 04/09/2026","date":"2026-09-04","sheet":"8–8","fileName":"LHD2609-JG00100_20260904.dwg","revisionCaveat":"Fecha de revisión tomada del nombre recibido; cajetines internos mantienen 02/07/2026 y algunos textos de plantilla.","sourceFileSha256":"b42eb027b7bc0b14c38d1d13514f4899b58a732aa8d0ba2ccf10fa2fc3192890"} | {"name":"Mortero HA-35 de alta resistencia sin retracción","status":"documentado","source":"Capa superior de 50 mm expresada en las secciones del fabricante"} | {"documented":[{"label":"Extensión local X","value":0.9,"unit":"m","source":"25A3/25CB, 25A3/E3A8, 1FEC2","status":"derivada del contorno CAD"},{"label":"Extensión local Y","value":0.8,"unit":"m","source":"25A3/25CB, 25A3/E3A8, 1FEC2","status":"derivada del contorno CAD"},{"label":"Cota inferior relativa adoptada","value":0.465,"unit":"m","source":"8–8","status":"interpretación con conflicto conservado"},{"label":"Cota superior relativa adoptada","value":0.515,"unit":"m","source":"8–8","status":"documentada / separación por material"}],"geometry":[{"label":"Extensión de la malla en X","value":1.0005760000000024,"unit":"m","source":"Geometría releída del IFC; datum absoluto de proceso provisional","status":"derivado"},{"label":"Extensión de la malla en Y","value":0.9151279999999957,"unit":"m","source":"Geometría releída del IFC; datum absoluto de proceso provisional","status":"derivado"},{"label":"Extensión de la malla en Z","value":0.050000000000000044,"unit":"m","source":"Geometría releída del IFC; datum absoluto de proceso provisional","status":"derivado"},{"label":"Cota inferior de visualización","value":286.565,"unit":"m","source":"Geometría releída del IFC; datum absoluto de proceso provisional","status":"derivado"},{"label":"Cota superior de visualización","value":286.615,"unit":"m","source":"Geometría releída del IFC; datum absoluto de proceso provisional","status":"derivado"}]} | ["Planta: −2,400 m. Sección 8–8: fondo −2,000 m, coronación de losa −1,400 m. Se adopta sección; pendiente de aclaración."] | {"Cota inferior relativa (m)":0.465,"Cota superior relativa (m)":0.515,"Cero absoluto de visualización (m)":286.1,"Estado del cero absoluto":"Provisional","Criterio":"Las cotas relativas proceden del dibujo; la equivalencia absoluta no está confirmada."} | F-LV1802A | ["LV1802A"] | [] | 8–8 | ["25A3/25CB","25A3/E3A8","1FEC2"] | F-LV1802A/Cimentación del vaporizador LV1802A · mortero de apoyo 4 | {"boundingBoxM":{"min":[34.472525,35.998446,1.565],"max":[35.473101,36.913574,1.615]},"extentsM":[1.000576,0.915128,0.05],"meshSurfaceM2":1.610001,"meshVolumeM3":0.036,"closedSolid":true,"basis":"Magnitudes de las mallas representadas, no cantidades certificadas de obra, compra o fabricación. Las partes pueden compartir superficies; no se suman como un despiece de materiales."} | {"profileId":"grout_ha35","name":"Grout HA-35 sin retracción","materialName":"Mortero HA-35 de alta resistencia sin retracción","physicalMaterialStatus":"documentado","physicalMaterialSource":"Capa superior de 50 mm expresada en las secciones del fabricante","appearanceStatus":"criterio_visual","appearanceBasis":"Interpretación visual del material documental; el acabado, tono y parámetros PBR no son una especificación contractual.","note":"La apariencia gráfica no modifica ni confirma la especificación física del material."} | {"elementId":"found_0904_b15308da61d013","ifcGuid":"0tkfsGAOnNLO$SMXobBTqW","ifcClass":"IfcSlab","buildingId":"process_plant","buildingName":"Zona de separación de aire","sourceDocumentId":"LHD2609-JG00100-20260904","sourceRepresentationKind":"foundation"} | {"profileId":"grout_ha35","name":"Grout HA-35 sin retracción","status":"criterio_visual","basis":"Interpretación visual del material documental; el acabado, tono y parámetros PBR no son una especificación contractual.","physicalMaterialUnchanged":true} | LV1802A | 25A3/25CB, 25A3/E3A8, 1FEC2 | Mortero HA-35 de alta resistencia sin retracción | 0.465 | 0.515 | 0.72 | 0.036 | Sección y contornos del fabricante; incidencias conservadas | Grout HA-35 sin retracción | found_0904_b15308da61d013 | documentado | Capa superior de 50 mm expresada en las secciones del fabricante | 0.9 | 0.8 | grout_ha35 | [0.792157,0.776471,0.721569] | 0.94 | Planta: −2,400 m. Sección 8–8: fondo −2,000 m, coronación de losa −1,400 m. Se adopta sección; pendiente de aclaración.
Cimentación del vaporizador LV1802A · mortero de apoyo 5 | Mortero HA-35 de alta resistencia sin retracción | 1.00058 | 0.915128 | 0.05 | 286.565 | 286.615 | 1.61 | 0.036 | {"documentId":"LHD2609-JG00100-20260904","title":"Cimentaciones de equipos y pedestales del fabricante · revisión recibida 04/09/2026","date":"2026-09-04","sheet":"8–8","fileName":"LHD2609-JG00100_20260904.dwg","revisionCaveat":"Fecha de revisión tomada del nombre recibido; cajetines internos mantienen 02/07/2026 y algunos textos de plantilla.","sourceFileSha256":"b42eb027b7bc0b14c38d1d13514f4899b58a732aa8d0ba2ccf10fa2fc3192890"} | {"name":"Mortero HA-35 de alta resistencia sin retracción","status":"documentado","source":"Capa superior de 50 mm expresada en las secciones del fabricante"} | {"documented":[{"label":"Extensión local X","value":0.9,"unit":"m","source":"25A3/25CB, 25A3/E3A8, 1FEC2","status":"derivada del contorno CAD"},{"label":"Extensión local Y","value":0.8,"unit":"m","source":"25A3/25CB, 25A3/E3A8, 1FEC2","status":"derivada del contorno CAD"},{"label":"Cota inferior relativa adoptada","value":0.465,"unit":"m","source":"8–8","status":"interpretación con conflicto conservado"},{"label":"Cota superior relativa adoptada","value":0.515,"unit":"m","source":"8–8","status":"documentada / separación por material"}],"geometry":[{"label":"Extensión de la malla en X","value":1.0005760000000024,"unit":"m","source":"Geometría releída del IFC; datum absoluto de proceso provisional","status":"derivado"},{"label":"Extensión de la malla en Y","value":0.9151280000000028,"unit":"m","source":"Geometría releída del IFC; datum absoluto de proceso provisional","status":"derivado"},{"label":"Extensión de la malla en Z","value":0.050000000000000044,"unit":"m","source":"Geometría releída del IFC; datum absoluto de proceso provisional","status":"derivado"},{"label":"Cota inferior de visualización","value":286.565,"unit":"m","source":"Geometría releída del IFC; datum absoluto de proceso provisional","status":"derivado"},{"label":"Cota superior de visualización","value":286.615,"unit":"m","source":"Geometría releída del IFC; datum absoluto de proceso provisional","status":"derivado"}]} | ["Planta: −2,400 m. Sección 8–8: fondo −2,000 m, coronación de losa −1,400 m. Se adopta sección; pendiente de aclaración."] | {"Cota inferior relativa (m)":0.465,"Cota superior relativa (m)":0.515,"Cero absoluto de visualización (m)":286.1,"Estado del cero absoluto":"Provisional","Criterio":"Las cotas relativas proceden del dibujo; la equivalencia absoluta no está confirmada."} | F-LV1802A | ["LV1802A"] | [] | 8–8 | ["25A3/25CB","25A3/E3A8","1FEC2"] | F-LV1802A/Cimentación del vaporizador LV1802A · mortero de apoyo 5 | {"boundingBoxM":{"min":[35.705241,36.682924,1.565],"max":[36.705817,37.598052,1.615]},"extentsM":[1.000576,0.915128,0.05],"meshSurfaceM2":1.610001,"meshVolumeM3":0.036,"closedSolid":true,"basis":"Magnitudes de las mallas representadas, no cantidades certificadas de obra, compra o fabricación. Las partes pueden compartir superficies; no se suman como un despiece de materiales."} | {"profileId":"grout_ha35","name":"Grout HA-35 sin retracción","materialName":"Mortero HA-35 de alta resistencia sin retracción","physicalMaterialStatus":"documentado","physicalMaterialSource":"Capa superior de 50 mm expresada en las secciones del fabricante","appearanceStatus":"criterio_visual","appearanceBasis":"Interpretación visual del material documental; el acabado, tono y parámetros PBR no son una especificación contractual.","note":"La apariencia gráfica no modifica ni confirma la especificación física del material."} | {"elementId":"found_0904_1b61a85c3e5459","ifcGuid":"0sjJK9PxjPIPJIkj5Z2Z6d","ifcClass":"IfcSlab","buildingId":"process_plant","buildingName":"Zona de separación de aire","sourceDocumentId":"LHD2609-JG00100-20260904","sourceRepresentationKind":"foundation"} | {"profileId":"grout_ha35","name":"Grout HA-35 sin retracción","status":"criterio_visual","basis":"Interpretación visual del material documental; el acabado, tono y parámetros PBR no son una especificación contractual.","physicalMaterialUnchanged":true} | LV1802A | 25A3/25CB, 25A3/E3A8, 1FEC2 | Mortero HA-35 de alta resistencia sin retracción | 0.465 | 0.515 | 0.72 | 0.036 | Sección y contornos del fabricante; incidencias conservadas | Grout HA-35 sin retracción | found_0904_1b61a85c3e5459 | documentado | Capa superior de 50 mm expresada en las secciones del fabricante | 0.9 | 0.8 | grout_ha35 | [0.792157,0.776471,0.721569] | 0.94 | Planta: −2,400 m. Sección 8–8: fondo −2,000 m, coronación de losa −1,400 m. Se adopta sección; pendiente de aclaración.
Cimentación del vaporizador LV1802B · capa de limpieza | Hormigón de limpieza HA-20 | 4.6853 | 4.11793 | 0.1 | 284 | 284.1 | 31.8556 | 1.51466 | {"documentId":"LHD2609-JG00100-20260904","title":"Cimentaciones de equipos y pedestales del fabricante · revisión recibida 04/09/2026","date":"2026-09-04","sheet":"8–8","fileName":"LHD2609-JG00100_20260904.dwg","revisionCaveat":"Fecha de revisión tomada del nombre recibido; cajetines internos mantienen 02/07/2026 y algunos textos de plantilla.","sourceFileSha256":"b42eb027b7bc0b14c38d1d13514f4899b58a732aa8d0ba2ccf10fa2fc3192890"} | {"name":"Hormigón de limpieza HA-20","status":"documentado","source":"Secciones del fabricante: capa de limpieza de 100 mm; nota 2CED5"} | {"documented":[{"label":"Extensión local X","value":4.238,"unit":"m","source":"2718/25CB, 2718/E3A8, 1FEC2","status":"derivada del contorno CAD"},{"label":"Extensión local Y","value":3.574,"unit":"m","source":"2718/25CB, 2718/E3A8, 1FEC2","status":"derivada del contorno CAD"},{"label":"Cota inferior relativa adoptada","value":-2.1,"unit":"m","source":"8–8","status":"interpretación con conflicto conservado"},{"label":"Cota superior relativa adoptada","value":-2,"unit":"m","source":"8–8","status":"documentada / separación por material"}],"geometry":[{"label":"Extensión de la malla en X","value":4.685298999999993,"unit":"m","source":"Geometría releída del IFC; datum absoluto de proceso provisional","status":"derivado"},{"label":"Extensión de la malla en Y","value":4.117926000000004,"unit":"m","source":"Geometría releída del IFC; datum absoluto de proceso provisional","status":"derivado"},{"label":"Extensión de la malla en Z","value":0.09999999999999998,"unit":"m","source":"Geometría releída del IFC; datum absoluto de proceso provisional","status":"derivado"},{"label":"Cota inferior de visualización","value":284.0,"unit":"m","source":"Geometría releída del IFC; datum absoluto de proceso provisional","status":"derivado"},{"label":"Cota superior de visualización","value":284.1,"unit":"m","source":"Geometría releída del IFC; datum absoluto de proceso provisional","status":"derivado"}]} | ["Planta: −2,400 m. Sección 8–8: fondo −2,000 m, coronación de losa −1,400 m. Se adopta sección; pendiente de aclaración."] | {"Cota inferior relativa (m)":-2.1,"Cota superior relativa (m)":-2,"Cero absoluto de visualización (m)":286.1,"Estado del cero absoluto":"Provisional","Criterio":"Las cotas relativas proceden del dibujo; la equivalencia absoluta no está confirmada."} | F-LV1802B | ["LV1802B"] | [] | 8–8 | ["2718/25CB","2718/E3A8","1FEC2"] | F-LV1802B/Cimentación del vaporizador LV1802B · capa de limpieza | {"boundingBoxM":{"min":[39.371447,34.466505,-1.0],"max":[44.056746,38.584431,-0.9]},"extentsM":[4.685299,4.117926,0.1],"meshSurfaceM2":31.855635,"meshVolumeM3":1.514662,"closedSolid":true,"basis":"Magnitudes de las mallas representadas, no cantidades certificadas de obra, compra o fabricación. Las partes pueden compartir superficies; no se suman como un despiece de materiales."} | {"profileId":"concrete_ha20","name":"Hormigón de limpieza HA-20","materialName":"Hormigón de limpieza HA-20","physicalMaterialStatus":"documentado","physicalMaterialSource":"Secciones del fabricante: capa de limpieza de 100 mm; nota 2CED5","appearanceStatus":"criterio_visual","appearanceBasis":"Interpretación visual del material documental; el acabado, tono y parámetros PBR no son una especificación contractual.","note":"La apariencia gráfica no modifica ni confirma la especificación física del material."} | {"elementId":"found_0904_1b97527a137752","ifcGuid":"10UBkLLUDVoRKM42jR9w8t","ifcClass":"IfcSlab","buildingId":"process_plant","buildingName":"Zona de separación de aire","sourceDocumentId":"LHD2609-JG00100-20260904","sourceRepresentationKind":"foundation"} | {"profileId":"concrete_ha20","name":"Hormigón de limpieza HA-20","status":"criterio_visual","basis":"Interpretación visual del material documental; el acabado, tono y parámetros PBR no son una especificación contractual.","physicalMaterialUnchanged":true} | LV1802B | 2718/25CB, 2718/E3A8, 1FEC2 | Hormigón de limpieza HA-20 | -2.1 | -2 | 15.1466 | 1.51466 | Sección y contornos del fabricante; incidencias conservadas | Hormigón de limpieza HA-20 | found_0904_1b97527a137752 | documentado | Secciones del fabricante: capa de limpieza de 100 mm; nota 2CED5 | 4.238 | 3.574 | concrete_ha20 | [0.721569,0.709804,0.658824] | 0.98 | Planta: −2,400 m. Sección 8–8: fondo −2,000 m, coronación de losa −1,400 m. Se adopta sección; pendiente de aclaración.
Cimentación del vaporizador LV1802B · mortero de apoyo 1 | Mortero HA-35 de alta resistencia sin retracción | 1.00058 | 0.915128 | 0.05 | 286.565 | 286.615 | 1.61 | 0.036 | {"documentId":"LHD2609-JG00100-20260904","title":"Cimentaciones de equipos y pedestales del fabricante · revisión recibida 04/09/2026","date":"2026-09-04","sheet":"8–8","fileName":"LHD2609-JG00100_20260904.dwg","revisionCaveat":"Fecha de revisión tomada del nombre recibido; cajetines internos mantienen 02/07/2026 y algunos textos de plantilla.","sourceFileSha256":"b42eb027b7bc0b14c38d1d13514f4899b58a732aa8d0ba2ccf10fa2fc3192890"} | {"name":"Mortero HA-35 de alta resistencia sin retracción","status":"documentado","source":"Capa superior de 50 mm expresada en las secciones del fabricante"} | {"documented":[{"label":"Extensión local X","value":0.9,"unit":"m","source":"2718/25CB, 2718/E3A8, 1FEC2","status":"derivada del contorno CAD"},{"label":"Extensión local Y","value":0.8,"unit":"m","source":"2718/25CB, 2718/E3A8, 1FEC2","status":"derivada del contorno CAD"},{"label":"Cota inferior relativa adoptada","value":0.465,"unit":"m","source":"8–8","status":"interpretación con conflicto conservado"},{"label":"Cota superior relativa adoptada","value":0.515,"unit":"m","source":"8–8","status":"documentada / separación por material"}],"geometry":[{"label":"Extensión de la malla en X","value":1.0005760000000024,"unit":"m","source":"Geometría releída del IFC; datum absoluto de proceso provisional","status":"derivado"},{"label":"Extensión de la malla en Y","value":0.9151279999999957,"unit":"m","source":"Geometría releída del IFC; datum absoluto de proceso provisional","status":"derivado"},{"label":"Extensión de la malla en Z","value":0.050000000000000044,"unit":"m","source":"Geometría releída del IFC; datum absoluto de proceso provisional","status":"derivado"},{"label":"Cota inferior de visualización","value":286.565,"unit":"m","source":"Geometría releída del IFC; datum absoluto de proceso provisional","status":"derivado"},{"label":"Cota superior de visualización","value":286.615,"unit":"m","source":"Geometría releída del IFC; datum absoluto de proceso provisional","status":"derivado"}]} | ["Planta: −2,400 m. Sección 8–8: fondo −2,000 m, coronación de losa −1,400 m. Se adopta sección; pendiente de aclaración."] | {"Cota inferior relativa (m)":0.465,"Cota superior relativa (m)":0.515,"Cero absoluto de visualización (m)":286.1,"Estado del cero absoluto":"Provisional","Criterio":"Las cotas relativas proceden del dibujo; la equivalencia absoluta no está confirmada."} | F-LV1802B | ["LV1802B"] | [] | 8–8 | ["2718/25CB","2718/E3A8","1FEC2"] | F-LV1802B/Cimentación del vaporizador LV1802B · mortero de apoyo 1 | {"boundingBoxM":{"min":[40.091068,37.218549,1.565],"max":[41.091644,38.133677,1.615]},"extentsM":[1.000576,0.915128,0.05],"meshSurfaceM2":1.61,"meshVolumeM3":0.036,"closedSolid":true,"basis":"Magnitudes de las mallas representadas, no cantidades certificadas de obra, compra o fabricación. Las partes pueden compartir superficies; no se suman como un despiece de materiales."} | {"profileId":"grout_ha35","name":"Grout HA-35 sin retracción","materialName":"Mortero HA-35 de alta resistencia sin retracción","physicalMaterialStatus":"documentado","physicalMaterialSource":"Capa superior de 50 mm expresada en las secciones del fabricante","appearanceStatus":"criterio_visual","appearanceBasis":"Interpretación visual del material documental; el acabado, tono y parámetros PBR no son una especificación contractual.","note":"La apariencia gráfica no modifica ni confirma la especificación física del material."} | {"elementId":"found_0904_85ed74c85618e3","ifcGuid":"0EaesrLijOk8P8$dpw3H1R","ifcClass":"IfcSlab","buildingId":"process_plant","buildingName":"Zona de separación de aire","sourceDocumentId":"LHD2609-JG00100-20260904","sourceRepresentationKind":"foundation"} | {"profileId":"grout_ha35","name":"Grout HA-35 sin retracción","status":"criterio_visual","basis":"Interpretación visual del material documental; el acabado, tono y parámetros PBR no son una especificación contractual.","physicalMaterialUnchanged":true} | LV1802B | 2718/25CB, 2718/E3A8, 1FEC2 | Mortero HA-35 de alta resistencia sin retracción | 0.465 | 0.515 | 0.72 | 0.036 | Sección y contornos del fabricante; incidencias conservadas | Grout HA-35 sin retracción | found_0904_85ed74c85618e3 | documentado | Capa superior de 50 mm expresada en las secciones del fabricante | 0.9 | 0.8 | grout_ha35 | [0.792157,0.776471,0.721569] | 0.94 | Planta: −2,400 m. Sección 8–8: fondo −2,000 m, coronación de losa −1,400 m. Se adopta sección; pendiente de aclaración.
Cimentación del vaporizador LV1802B · mortero de apoyo 2 | Mortero HA-35 de alta resistencia sin retracción | 1.00058 | 0.915128 | 0.05 | 286.565 | 286.615 | 1.61 | 0.036 | {"documentId":"LHD2609-JG00100-20260904","title":"Cimentaciones de equipos y pedestales del fabricante · revisión recibida 04/09/2026","date":"2026-09-04","sheet":"8–8","fileName":"LHD2609-JG00100_20260904.dwg","revisionCaveat":"Fecha de revisión tomada del nombre recibido; cajetines internos mantienen 02/07/2026 y algunos textos de plantilla.","sourceFileSha256":"b42eb027b7bc0b14c38d1d13514f4899b58a732aa8d0ba2ccf10fa2fc3192890"} | {"name":"Mortero HA-35 de alta resistencia sin retracción","status":"documentado","source":"Capa superior de 50 mm expresada en las secciones del fabricante"} | {"documented":[{"label":"Extensión local X","value":0.9,"unit":"m","source":"2718/25CB, 2718/E3A8, 1FEC2","status":"derivada del contorno CAD"},{"label":"Extensión local Y","value":0.8,"unit":"m","source":"2718/25CB, 2718/E3A8, 1FEC2","status":"derivada del contorno CAD"},{"label":"Cota inferior relativa adoptada","value":0.465,"unit":"m","source":"8–8","status":"interpretación con conflicto conservado"},{"label":"Cota superior relativa adoptada","value":0.515,"unit":"m","source":"8–8","status":"documentada / separación por material"}],"geometry":[{"label":"Extensión de la malla en X","value":1.0005760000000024,"unit":"m","source":"Geometría releída del IFC; datum absoluto de proceso provisional","status":"derivado"},{"label":"Extensión de la malla en Y","value":0.9151279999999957,"unit":"m","source":"Geometría releída del IFC; datum absoluto de proceso provisional","status":"derivado"},{"label":"Extensión de la malla en Z","value":0.050000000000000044,"unit":"m","source":"Geometría releída del IFC; datum absoluto de proceso provisional","status":"derivado"},{"label":"Cota inferior de visualización","value":286.565,"unit":"m","source":"Geometría releída del IFC; datum absoluto de proceso provisional","status":"derivado"},{"label":"Cota superior de visualización","value":286.615,"unit":"m","source":"Geometría releída del IFC; datum absoluto de proceso provisional","status":"derivado"}]} | ["Planta: −2,400 m. Sección 8–8: fondo −2,000 m, coronación de losa −1,400 m. Se adopta sección; pendiente de aclaración."] | {"Cota inferior relativa (m)":0.465,"Cota superior relativa (m)":0.515,"Cero absoluto de visualización (m)":286.1,"Estado del cero absoluto":"Provisional","Criterio":"Las cotas relativas proceden del dibujo; la equivalencia absoluta no está confirmada."} | F-LV1802B | ["LV1802B"] | [] | 8–8 | ["2718/25CB","2718/E3A8","1FEC2"] | F-LV1802B/Cimentación del vaporizador LV1802B · mortero de apoyo 2 | {"boundingBoxM":{"min":[42.605416,36.872863,1.565],"max":[43.605992,37.787991,1.615]},"extentsM":[1.000576,0.915128,0.05],"meshSurfaceM2":1.609999,"meshVolumeM3":0.036,"closedSolid":true,"basis":"Magnitudes de las mallas representadas, no cantidades certificadas de obra, compra o fabricación. Las partes pueden compartir superficies; no se suman como un despiece de materiales."} | {"profileId":"grout_ha35","name":"Grout HA-35 sin retracción","materialName":"Mortero HA-35 de alta resistencia sin retracción","physicalMaterialStatus":"documentado","physicalMaterialSource":"Capa superior de 50 mm expresada en las secciones del fabricante","appearanceStatus":"criterio_visual","appearanceBasis":"Interpretación visual del material documental; el acabado, tono y parámetros PBR no son una especificación contractual.","note":"La apariencia gráfica no modifica ni confirma la especificación física del material."} | {"elementId":"found_0904_7ef187068a20b2","ifcGuid":"1AqnEmn2jPvw9yRjorSbq$","ifcClass":"IfcSlab","buildingId":"process_plant","buildingName":"Zona de separación de aire","sourceDocumentId":"LHD2609-JG00100-20260904","sourceRepresentationKind":"foundation"} | {"profileId":"grout_ha35","name":"Grout HA-35 sin retracción","status":"criterio_visual","basis":"Interpretación visual del material documental; el acabado, tono y parámetros PBR no son una especificación contractual.","physicalMaterialUnchanged":true} | LV1802B | 2718/25CB, 2718/E3A8, 1FEC2 | Mortero HA-35 de alta resistencia sin retracción | 0.465 | 0.515 | 0.72 | 0.036 | Sección y contornos del fabricante; incidencias conservadas | Grout HA-35 sin retracción | found_0904_7ef187068a20b2 | documentado | Capa superior de 50 mm expresada en las secciones del fabricante | 0.9 | 0.8 | grout_ha35 | [0.792157,0.776471,0.721569] | 0.94 | Planta: −2,400 m. Sección 8–8: fondo −2,000 m, coronación de losa −1,400 m. Se adopta sección; pendiente de aclaración.
Cimentación del vaporizador LV1802B · mortero de apoyo 3 | Mortero HA-35 de alta resistencia sin retracción | 1.00058 | 0.915128 | 0.05 | 286.565 | 286.615 | 1.61 | 0.036 | {"documentId":"LHD2609-JG00100-20260904","title":"Cimentaciones de equipos y pedestales del fabricante · revisión recibida 04/09/2026","date":"2026-09-04","sheet":"8–8","fileName":"LHD2609-JG00100_20260904.dwg","revisionCaveat":"Fecha de revisión tomada del nombre recibido; cajetines internos mantienen 02/07/2026 y algunos textos de plantilla.","sourceFileSha256":"b42eb027b7bc0b14c38d1d13514f4899b58a732aa8d0ba2ccf10fa2fc3192890"} | {"name":"Mortero HA-35 de alta resistencia sin retracción","status":"documentado","source":"Capa superior de 50 mm expresada en las secciones del fabricante"} | {"documented":[{"label":"Extensión local X","value":0.9,"unit":"m","source":"2718/25CB, 2718/E3A8, 1FEC2","status":"derivada del contorno CAD"},{"label":"Extensión local Y","value":0.8,"unit":"m","source":"2718/25CB, 2718/E3A8, 1FEC2","status":"derivada del contorno CAD"},{"label":"Cota inferior relativa adoptada","value":0.465,"unit":"m","source":"8–8","status":"interpretación con conflicto conservado"},{"label":"Cota superior relativa adoptada","value":0.515,"unit":"m","source":"8–8","status":"documentada / separación por material"}],"geometry":[{"label":"Extensión de la malla en X","value":1.0005760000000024,"unit":"m","source":"Geometría releída del IFC; datum absoluto de proceso provisional","status":"derivado"},{"label":"Extensión de la malla en Y","value":0.9151279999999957,"unit":"m","source":"Geometría releída del IFC; datum absoluto de proceso provisional","status":"derivado"},{"label":"Extensión de la malla en Z","value":0.050000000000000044,"unit":"m","source":"Geometría releída del IFC; datum absoluto de proceso provisional","status":"derivado"},{"label":"Cota inferior de visualización","value":286.565,"unit":"m","source":"Geometría releída del IFC; datum absoluto de proceso provisional","status":"derivado"},{"label":"Cota superior de visualización","value":286.615,"unit":"m","source":"Geometría releída del IFC; datum absoluto de proceso provisional","status":"derivado"}]} | ["Planta: −2,400 m. Sección 8–8: fondo −2,000 m, coronación de losa −1,400 m. Se adopta sección; pendiente de aclaración."] | {"Cota inferior relativa (m)":0.465,"Cota superior relativa (m)":0.515,"Cero absoluto de visualización (m)":286.1,"Estado del cero absoluto":"Provisional","Criterio":"Las cotas relativas proceden del dibujo; la equivalencia absoluta no está confirmada."} | F-LV1802B | ["LV1802B"] | [] | 8–8 | ["2718/25CB","2718/E3A8","1FEC2"] | F-LV1802B/Cimentación del vaporizador LV1802B · mortero de apoyo 3 | {"boundingBoxM":{"min":[42.336549,34.917259,1.565],"max":[43.337125,35.832387,1.615]},"extentsM":[1.000576,0.915128,0.05],"meshSurfaceM2":1.61,"meshVolumeM3":0.036,"closedSolid":true,"basis":"Magnitudes de las mallas representadas, no cantidades certificadas de obra, compra o fabricación. Las partes pueden compartir superficies; no se suman como un despiece de materiales."} | {"profileId":"grout_ha35","name":"Grout HA-35 sin retracción","materialName":"Mortero HA-35 de alta resistencia sin retracción","physicalMaterialStatus":"documentado","physicalMaterialSource":"Capa superior de 50 mm expresada en las secciones del fabricante","appearanceStatus":"criterio_visual","appearanceBasis":"Interpretación visual del material documental; el acabado, tono y parámetros PBR no son una especificación contractual.","note":"La apariencia gráfica no modifica ni confirma la especificación física del material."} | {"elementId":"found_0904_c8566969e202a4","ifcGuid":"357_0UGL1UlfS6iQjo_6d3","ifcClass":"IfcSlab","buildingId":"process_plant","buildingName":"Zona de separación de aire","sourceDocumentId":"LHD2609-JG00100-20260904","sourceRepresentationKind":"foundation"} | {"profileId":"grout_ha35","name":"Grout HA-35 sin retracción","status":"criterio_visual","basis":"Interpretación visual del material documental; el acabado, tono y parámetros PBR no son una especificación contractual.","physicalMaterialUnchanged":true} | LV1802B | 2718/25CB, 2718/E3A8, 1FEC2 | Mortero HA-35 de alta resistencia sin retracción | 0.465 | 0.515 | 0.72 | 0.036 | Sección y contornos del fabricante; incidencias conservadas | Grout HA-35 sin retracción | found_0904_c8566969e202a4 | documentado | Capa superior de 50 mm expresada en las secciones del fabricante | 0.9 | 0.8 | grout_ha35 | [0.792157,0.776471,0.721569] | 0.94 | Planta: −2,400 m. Sección 8–8: fondo −2,000 m, coronación de losa −1,400 m. Se adopta sección; pendiente de aclaración.
Cimentación del vaporizador LV1802B · mortero de apoyo 4 | Mortero HA-35 de alta resistencia sin retracción | 1.00058 | 0.915128 | 0.05 | 286.565 | 286.615 | 1.61 | 0.036 | {"documentId":"LHD2609-JG00100-20260904","title":"Cimentaciones de equipos y pedestales del fabricante · revisión recibida 04/09/2026","date":"2026-09-04","sheet":"8–8","fileName":"LHD2609-JG00100_20260904.dwg","revisionCaveat":"Fecha de revisión tomada del nombre recibido; cajetines internos mantienen 02/07/2026 y algunos textos de plantilla.","sourceFileSha256":"b42eb027b7bc0b14c38d1d13514f4899b58a732aa8d0ba2ccf10fa2fc3192890"} | {"name":"Mortero HA-35 de alta resistencia sin retracción","status":"documentado","source":"Capa superior de 50 mm expresada en las secciones del fabricante"} | {"documented":[{"label":"Extensión local X","value":0.9,"unit":"m","source":"2718/25CB, 2718/E3A8, 1FEC2","status":"derivada del contorno CAD"},{"label":"Extensión local Y","value":0.8,"unit":"m","source":"2718/25CB, 2718/E3A8, 1FEC2","status":"derivada del contorno CAD"},{"label":"Cota inferior relativa adoptada","value":0.465,"unit":"m","source":"8–8","status":"interpretación con conflicto conservado"},{"label":"Cota superior relativa adoptada","value":0.515,"unit":"m","source":"8–8","status":"documentada / separación por material"}],"geometry":[{"label":"Extensión de la malla en X","value":1.0005760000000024,"unit":"m","source":"Geometría releída del IFC; datum absoluto de proceso provisional","status":"derivado"},{"label":"Extensión de la malla en Y","value":0.9151279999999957,"unit":"m","source":"Geometría releída del IFC; datum absoluto de proceso provisional","status":"derivado"},{"label":"Extensión de la malla en Z","value":0.050000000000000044,"unit":"m","source":"Geometría releída del IFC; datum absoluto de proceso provisional","status":"derivado"},{"label":"Cota inferior de visualización","value":286.565,"unit":"m","source":"Geometría releída del IFC; datum absoluto de proceso provisional","status":"derivado"},{"label":"Cota superior de visualización","value":286.615,"unit":"m","source":"Geometría releída del IFC; datum absoluto de proceso provisional","status":"derivado"}]} | ["Planta: −2,400 m. Sección 8–8: fondo −2,000 m, coronación de losa −1,400 m. Se adopta sección; pendiente de aclaración."] | {"Cota inferior relativa (m)":0.465,"Cota superior relativa (m)":0.515,"Cero absoluto de visualización (m)":286.1,"Estado del cero absoluto":"Provisional","Criterio":"Las cotas relativas proceden del dibujo; la equivalencia absoluta no está confirmada."} | F-LV1802B | ["LV1802B"] | [] | 8–8 | ["2718/25CB","2718/E3A8","1FEC2"] | F-LV1802B/Cimentación del vaporizador LV1802B · mortero de apoyo 4 | {"boundingBoxM":{"min":[39.822201,35.262945,1.565],"max":[40.822777,36.178073,1.615]},"extentsM":[1.000576,0.915128,0.05],"meshSurfaceM2":1.61,"meshVolumeM3":0.036,"closedSolid":true,"basis":"Magnitudes de las mallas representadas, no cantidades certificadas de obra, compra o fabricación. Las partes pueden compartir superficies; no se suman como un despiece de materiales."} | {"profileId":"grout_ha35","name":"Grout HA-35 sin retracción","materialName":"Mortero HA-35 de alta resistencia sin retracción","physicalMaterialStatus":"documentado","physicalMaterialSource":"Capa superior de 50 mm expresada en las secciones del fabricante","appearanceStatus":"criterio_visual","appearanceBasis":"Interpretación visual del material documental; el acabado, tono y parámetros PBR no son una especificación contractual.","note":"La apariencia gráfica no modifica ni confirma la especificación física del material."} | {"elementId":"found_0904_9636fe48a7f337","ifcGuid":"3g3noQbxrGhubdOZJPn7dM","ifcClass":"IfcSlab","buildingId":"process_plant","buildingName":"Zona de separación de aire","sourceDocumentId":"LHD2609-JG00100-20260904","sourceRepresentationKind":"foundation"} | {"profileId":"grout_ha35","name":"Grout HA-35 sin retracción","status":"criterio_visual","basis":"Interpretación visual del material documental; el acabado, tono y parámetros PBR no son una especificación contractual.","physicalMaterialUnchanged":true} | LV1802B | 2718/25CB, 2718/E3A8, 1FEC2 | Mortero HA-35 de alta resistencia sin retracción | 0.465 | 0.515 | 0.72 | 0.036 | Sección y contornos del fabricante; incidencias conservadas | Grout HA-35 sin retracción | found_0904_9636fe48a7f337 | documentado | Capa superior de 50 mm expresada en las secciones del fabricante | 0.9 | 0.8 | grout_ha35 | [0.792157,0.776471,0.721569] | 0.94 | Planta: −2,400 m. Sección 8–8: fondo −2,000 m, coronación de losa −1,400 m. Se adopta sección; pendiente de aclaración.
Cimentación del vaporizador LV1802B · mortero de apoyo 5 | Mortero HA-35 de alta resistencia sin retracción | 1.00058 | 0.915128 | 0.05 | 286.565 | 286.615 | 1.61 | 0.036 | {"documentId":"LHD2609-JG00100-20260904","title":"Cimentaciones de equipos y pedestales del fabricante · revisión recibida 04/09/2026","date":"2026-09-04","sheet":"8–8","fileName":"LHD2609-JG00100_20260904.dwg","revisionCaveat":"Fecha de revisión tomada del nombre recibido; cajetines internos mantienen 02/07/2026 y algunos textos de plantilla.","sourceFileSha256":"b42eb027b7bc0b14c38d1d13514f4899b58a732aa8d0ba2ccf10fa2fc3192890"} | {"name":"Mortero HA-35 de alta resistencia sin retracción","status":"documentado","source":"Capa superior de 50 mm expresada en las secciones del fabricante"} | {"documented":[{"label":"Extensión local X","value":0.9,"unit":"m","source":"2718/25CB, 2718/E3A8, 1FEC2","status":"derivada del contorno CAD"},{"label":"Extensión local Y","value":0.8,"unit":"m","source":"2718/25CB, 2718/E3A8, 1FEC2","status":"derivada del contorno CAD"},{"label":"Cota inferior relativa adoptada","value":0.465,"unit":"m","source":"8–8","status":"interpretación con conflicto conservado"},{"label":"Cota superior relativa adoptada","value":0.515,"unit":"m","source":"8–8","status":"documentada / separación por material"}],"geometry":[{"label":"Extensión de la malla en X","value":1.0005760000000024,"unit":"m","source":"Geometría releída del IFC; datum absoluto de proceso provisional","status":"derivado"},{"label":"Extensión de la malla en Y","value":0.9151280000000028,"unit":"m","source":"Geometría releída del IFC; datum absoluto de proceso provisional","status":"derivado"},{"label":"Extensión de la malla en Z","value":0.050000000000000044,"unit":"m","source":"Geometría releída del IFC; datum absoluto de proceso provisional","status":"derivado"},{"label":"Cota inferior de visualización","value":286.565,"unit":"m","source":"Geometría releída del IFC; datum absoluto de proceso provisional","status":"derivado"},{"label":"Cota superior de visualización","value":286.615,"unit":"m","source":"Geometría releída del IFC; datum absoluto de proceso provisional","status":"derivado"}]} | ["Planta: −2,400 m. Sección 8–8: fondo −2,000 m, coronación de losa −1,400 m. Se adopta sección; pendiente de aclaración."] | {"Cota inferior relativa (m)":0.465,"Cota superior relativa (m)":0.515,"Cero absoluto de visualización (m)":286.1,"Estado del cero absoluto":"Provisional","Criterio":"Las cotas relativas proceden del dibujo; la equivalencia absoluta no está confirmada."} | F-LV1802B | ["LV1802B"] | [] | 8–8 | ["2718/25CB","2718/E3A8","1FEC2"] | F-LV1802B/Cimentación del vaporizador LV1802B · mortero de apoyo 5 | {"boundingBoxM":{"min":[41.054918,35.947423,1.565],"max":[42.055494,36.862551,1.615]},"extentsM":[1.000576,0.915128,0.05],"meshSurfaceM2":1.609999,"meshVolumeM3":0.036,"closedSolid":true,"basis":"Magnitudes de las mallas representadas, no cantidades certificadas de obra, compra o fabricación. Las partes pueden compartir superficies; no se suman como un despiece de materiales."} | {"profileId":"grout_ha35","name":"Grout HA-35 sin retracción","materialName":"Mortero HA-35 de alta resistencia sin retracción","physicalMaterialStatus":"documentado","physicalMaterialSource":"Capa superior de 50 mm expresada en las secciones del fabricante","appearanceStatus":"criterio_visual","appearanceBasis":"Interpretación visual del material documental; el acabado, tono y parámetros PBR no son una especificación contractual.","note":"La apariencia gráfica no modifica ni confirma la especificación física del material."} | {"elementId":"found_0904_71372f1c9ab124","ifcGuid":"3srJsh6zHR3OHNAGs6LD$W","ifcClass":"IfcSlab","buildingId":"process_plant","buildingName":"Zona de separación de aire","sourceDocumentId":"LHD2609-JG00100-20260904","sourceRepresentationKind":"foundation"} | {"profileId":"grout_ha35","name":"Grout HA-35 sin retracción","status":"criterio_visual","basis":"Interpretación visual del material documental; el acabado, tono y parámetros PBR no son una especificación contractual.","physicalMaterialUnchanged":true} | LV1802B | 2718/25CB, 2718/E3A8, 1FEC2 | Mortero HA-35 de alta resistencia sin retracción | 0.465 | 0.515 | 0.72 | 0.036 | Sección y contornos del fabricante; incidencias conservadas | Grout HA-35 sin retracción | found_0904_71372f1c9ab124 | documentado | Capa superior de 50 mm expresada en las secciones del fabricante | 0.9 | 0.8 | grout_ha35 | [0.792157,0.776471,0.721569] | 0.94 | Planta: −2,400 m. Sección 8–8: fondo −2,000 m, coronación de losa −1,400 m. Se adopta sección; pendiente de aclaración.
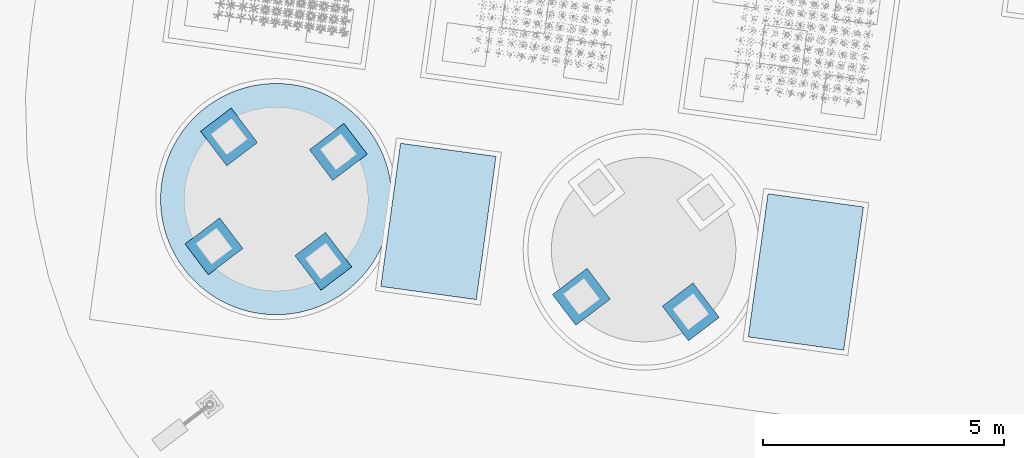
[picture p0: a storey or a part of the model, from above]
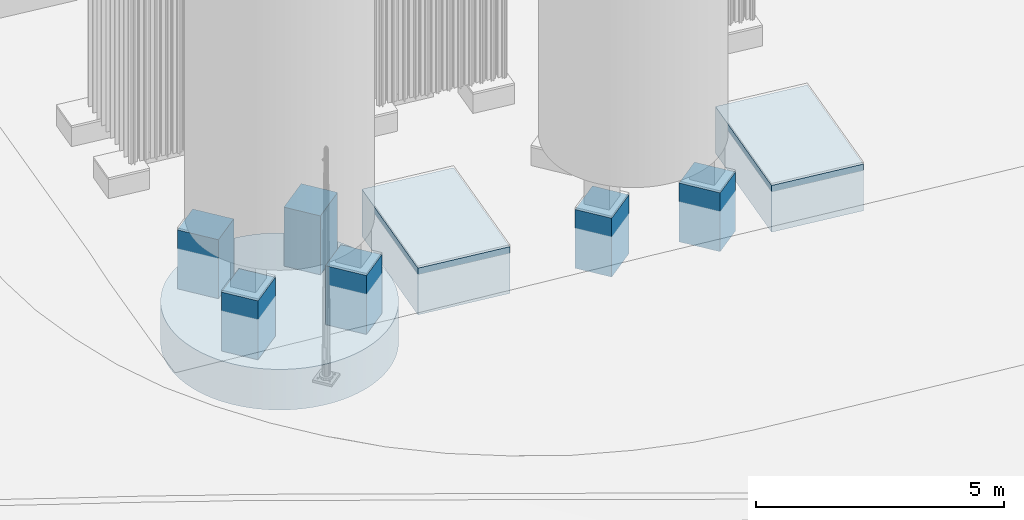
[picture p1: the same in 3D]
Properties of the parts of a building model (IFC4), part 106 of 134

# IfcSlab: Cimentación industrial (108)
Name | Material | Extensión de la malla en X (m) = ExtensionX (m) | Extensión de la malla en Y (m) = ExtensionY (m) | Extensión de la malla en Z (m) = ExtensionZ (m) = Espesor o altura real de sección (m) | Cota inferior de visualización (m) | Cota superior de visualización (m) | SuperficieDeLaMalla (m2) | VolumenGeometrico (m3) | JH_InformacionBIM, source = DocumentoFuente | material | dimensions | issues = IncidenciasPendientes | positioning = PosicionYEstado | assemblyId = Conjunto de cimentación | equipmentIds | supportPositionIds | sectionRef = Sección de referencia | sourceCadHandles | stableElementKey | geometryMetrics | materialAppearance | visualizationIdentity | appearance | Equipos asociados | Identificadores CAD de referencia | JH_Trazabilidad, Material = name | Cota inferior relativa (m) = Cota inferior relativa adoptada (m) | Cota superior relativa (m) = Cota superior relativa adoptada (m) | Área de planta (m²) | Volumen geométrico (m³) | Estado de la geometría | Acabado de visualización = Acabado | Identificador | status | JH_EvidenciaDeMaterial, source | Extensión local X (m) | Extensión local Y (m) | Perfil | ColorRGB | Rugosidad | Incidencias de origen
Cimentación del vaporizador LV1802C · capa de limpieza | Hormigón de limpieza HA-20 | 4.6853 | 4.11793 | 0.1 | 284 | 284.1 | 31.8556 | 1.51466 | {"documentId":"LHD2609-JG00100-20260904","title":"Cimentaciones de equipos y pedestales del fabricante · revisión recibida 04/09/2026","date":"2026-09-04","sheet":"8–8","fileName":"LHD2609-JG00100_20260904.dwg","revisionCaveat":"Fecha de revisión tomada del nombre recibido; cajetines internos mantienen 02/07/2026 y algunos textos de plantilla.","sourceFileSha256":"b42eb027b7bc0b14c38d1d13514f4899b58a732aa8d0ba2ccf10fa2fc3192890"} | {"name":"Hormigón de limpieza HA-20","status":"documentado","source":"Secciones del fabricante: capa de limpieza de 100 mm; nota 2CED5"} | {"documented":[{"label":"Extensión local X","value":4.238,"unit":"m","source":"2719/25CB, 2719/E3A8, 1FEC2","status":"derivada del contorno CAD"},{"label":"Extensión local Y","value":3.574,"unit":"m","source":"2719/25CB, 2719/E3A8, 1FEC2","status":"derivada del contorno CAD"},{"label":"Cota inferior relativa adoptada","value":-2.1,"unit":"m","source":"8–8","status":"interpretación con conflicto conservado"},{"label":"Cota superior relativa adoptada","value":-2,"unit":"m","source":"8–8","status":"documentada / separación por material"}],"geometry":[{"label":"Extensión de la malla en X","value":4.685297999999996,"unit":"m","source":"Geometría releída del IFC; datum absoluto de proceso provisional","status":"derivado"},{"label":"Extensión de la malla en Y","value":4.117926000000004,"unit":"m","source":"Geometría releída del IFC; datum absoluto de proceso provisional","status":"derivado"},{"label":"Extensión de la malla en Z","value":0.09999999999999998,"unit":"m","source":"Geometría releída del IFC; datum absoluto de proceso provisional","status":"derivado"},{"label":"Cota inferior de visualización","value":284.0,"unit":"m","source":"Geometría releída del IFC; datum absoluto de proceso provisional","status":"derivado"},{"label":"Cota superior de visualización","value":284.1,"unit":"m","source":"Geometría releída del IFC; datum absoluto de proceso provisional","status":"derivado"}]} | ["Planta: −2,400 m. Sección 8–8: fondo −2,000 m, coronación de losa −1,400 m. Se adopta sección; pendiente de aclaración."] | {"Cota inferior relativa (m)":-2.1,"Cota superior relativa (m)":-2,"Cero absoluto de visualización (m)":286.1,"Estado del cero absoluto":"Provisional","Criterio":"Las cotas relativas proceden del dibujo; la equivalencia absoluta no está confirmada."} | F-LV1802C | ["LV1802C"] | [] | 8–8 | ["2719/25CB","2719/E3A8","1FEC2"] | F-LV1802C/Cimentación del vaporizador LV1802C · capa de limpieza | {"boundingBoxM":{"min":[44.721124,33.731004,-1.0],"max":[49.406422,37.84893,-0.9]},"extentsM":[4.685298,4.117926,0.1],"meshSurfaceM2":31.855624,"meshVolumeM3":1.514661,"closedSolid":true,"basis":"Magnitudes de las mallas representadas, no cantidades certificadas de obra, compra o fabricación. Las partes pueden compartir superficies; no se suman como un despiece de materiales."} | {"profileId":"concrete_ha20","name":"Hormigón de limpieza HA-20","materialName":"Hormigón de limpieza HA-20","physicalMaterialStatus":"documentado","physicalMaterialSource":"Secciones del fabricante: capa de limpieza de 100 mm; nota 2CED5","appearanceStatus":"criterio_visual","appearanceBasis":"Interpretación visual del material documental; el acabado, tono y parámetros PBR no son una especificación contractual.","note":"La apariencia gráfica no modifica ni confirma la especificación física del material."} | {"elementId":"found_0904_fe1e9d7a392163","ifcGuid":"23xIVCMYvRifwABwOtJLU7","ifcClass":"IfcSlab","buildingId":"process_plant","buildingName":"Zona de separación de aire","sourceDocumentId":"LHD2609-JG00100-20260904","sourceRepresentationKind":"foundation"} | {"profileId":"concrete_ha20","name":"Hormigón de limpieza HA-20","status":"criterio_visual","basis":"Interpretación visual del material documental; el acabado, tono y parámetros PBR no son una especificación contractual.","physicalMaterialUnchanged":true} | LV1802C | 2719/25CB, 2719/E3A8, 1FEC2 | Hormigón de limpieza HA-20 | -2.1 | -2 | 15.1466 | 1.51466 | Sección y contornos del fabricante; incidencias conservadas | Hormigón de limpieza HA-20 | found_0904_fe1e9d7a392163 | documentado | Secciones del fabricante: capa de limpieza de 100 mm; nota 2CED5 | 4.238 | 3.574 | concrete_ha20 | [0.721569,0.709804,0.658824] | 0.98 | Planta: −2,400 m. Sección 8–8: fondo −2,000 m, coronación de losa −1,400 m. Se adopta sección; pendiente de aclaración.
Cimentación del vaporizador LV1802C · mortero de apoyo 1 | Mortero HA-35 de alta resistencia sin retracción | 1.00058 | 0.915129 | 0.05 | 286.565 | 286.615 | 1.61 | 0.036 | {"documentId":"LHD2609-JG00100-20260904","title":"Cimentaciones de equipos y pedestales del fabricante · revisión recibida 04/09/2026","date":"2026-09-04","sheet":"8–8","fileName":"LHD2609-JG00100_20260904.dwg","revisionCaveat":"Fecha de revisión tomada del nombre recibido; cajetines internos mantienen 02/07/2026 y algunos textos de plantilla.","sourceFileSha256":"b42eb027b7bc0b14c38d1d13514f4899b58a732aa8d0ba2ccf10fa2fc3192890"} | {"name":"Mortero HA-35 de alta resistencia sin retracción","status":"documentado","source":"Capa superior de 50 mm expresada en las secciones del fabricante"} | {"documented":[{"label":"Extensión local X","value":0.9,"unit":"m","source":"2719/25CB, 2719/E3A8, 1FEC2","status":"derivada del contorno CAD"},{"label":"Extensión local Y","value":0.8,"unit":"m","source":"2719/25CB, 2719/E3A8, 1FEC2","status":"derivada del contorno CAD"},{"label":"Cota inferior relativa adoptada","value":0.465,"unit":"m","source":"8–8","status":"interpretación con conflicto conservado"},{"label":"Cota superior relativa adoptada","value":0.515,"unit":"m","source":"8–8","status":"documentada / separación por material"}],"geometry":[{"label":"Extensión de la malla en X","value":1.0005759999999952,"unit":"m","source":"Geometría releída del IFC; datum absoluto de proceso provisional","status":"derivado"},{"label":"Extensión de la malla en Y","value":0.9151290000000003,"unit":"m","source":"Geometría releída del IFC; datum absoluto de proceso provisional","status":"derivado"},{"label":"Extensión de la malla en Z","value":0.050000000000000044,"unit":"m","source":"Geometría releída del IFC; datum absoluto de proceso provisional","status":"derivado"},{"label":"Cota inferior de visualización","value":286.565,"unit":"m","source":"Geometría releída del IFC; datum absoluto de proceso provisional","status":"derivado"},{"label":"Cota superior de visualización","value":286.615,"unit":"m","source":"Geometría releída del IFC; datum absoluto de proceso provisional","status":"derivado"}]} | ["Planta: −2,400 m. Sección 8–8: fondo −2,000 m, coronación de losa −1,400 m. Se adopta sección; pendiente de aclaración."] | {"Cota inferior relativa (m)":0.465,"Cota superior relativa (m)":0.515,"Cero absoluto de visualización (m)":286.1,"Estado del cero absoluto":"Provisional","Criterio":"Las cotas relativas proceden del dibujo; la equivalencia absoluta no está confirmada."} | F-LV1802C | ["LV1802C"] | [] | 8–8 | ["2719/25CB","2719/E3A8","1FEC2"] | F-LV1802C/Cimentación del vaporizador LV1802C · mortero de apoyo 1 | {"boundingBoxM":{"min":[45.440744,36.483047,1.565],"max":[46.44132,37.398176,1.615]},"extentsM":[1.000576,0.915129,0.05],"meshSurfaceM2":1.610001,"meshVolumeM3":0.036,"closedSolid":true,"basis":"Magnitudes de las mallas representadas, no cantidades certificadas de obra, compra o fabricación. Las partes pueden compartir superficies; no se suman como un despiece de materiales."} | {"profileId":"grout_ha35","name":"Grout HA-35 sin retracción","materialName":"Mortero HA-35 de alta resistencia sin retracción","physicalMaterialStatus":"documentado","physicalMaterialSource":"Capa superior de 50 mm expresada en las secciones del fabricante","appearanceStatus":"criterio_visual","appearanceBasis":"Interpretación visual del material documental; el acabado, tono y parámetros PBR no son una especificación contractual.","note":"La apariencia gráfica no modifica ni confirma la especificación física del material."} | {"elementId":"found_0904_aa0c02564490dd","ifcGuid":"0hcCtKxFXMG8_R$Wnlv$UL","ifcClass":"IfcSlab","buildingId":"process_plant","buildingName":"Zona de separación de aire","sourceDocumentId":"LHD2609-JG00100-20260904","sourceRepresentationKind":"foundation"} | {"profileId":"grout_ha35","name":"Grout HA-35 sin retracción","status":"criterio_visual","basis":"Interpretación visual del material documental; el acabado, tono y parámetros PBR no son una especificación contractual.","physicalMaterialUnchanged":true} | LV1802C | 2719/25CB, 2719/E3A8, 1FEC2 | Mortero HA-35 de alta resistencia sin retracción | 0.465 | 0.515 | 0.72 | 0.036 | Sección y contornos del fabricante; incidencias conservadas | Grout HA-35 sin retracción | found_0904_aa0c02564490dd | documentado | Capa superior de 50 mm expresada en las secciones del fabricante | 0.9 | 0.8 | grout_ha35 | [0.792157,0.776471,0.721569] | 0.94 | Planta: −2,400 m. Sección 8–8: fondo −2,000 m, coronación de losa −1,400 m. Se adopta sección; pendiente de aclaración.
Cimentación del vaporizador LV1802C · mortero de apoyo 2 | Mortero HA-35 de alta resistencia sin retracción | 1.00058 | 0.915128 | 0.05 | 286.565 | 286.615 | 1.61 | 0.036 | {"documentId":"LHD2609-JG00100-20260904","title":"Cimentaciones de equipos y pedestales del fabricante · revisión recibida 04/09/2026","date":"2026-09-04","sheet":"8–8","fileName":"LHD2609-JG00100_20260904.dwg","revisionCaveat":"Fecha de revisión tomada del nombre recibido; cajetines internos mantienen 02/07/2026 y algunos textos de plantilla.","sourceFileSha256":"b42eb027b7bc0b14c38d1d13514f4899b58a732aa8d0ba2ccf10fa2fc3192890"} | {"name":"Mortero HA-35 de alta resistencia sin retracción","status":"documentado","source":"Capa superior de 50 mm expresada en las secciones del fabricante"} | {"documented":[{"label":"Extensión local X","value":0.9,"unit":"m","source":"2719/25CB, 2719/E3A8, 1FEC2","status":"derivada del contorno CAD"},{"label":"Extensión local Y","value":0.8,"unit":"m","source":"2719/25CB, 2719/E3A8, 1FEC2","status":"derivada del contorno CAD"},{"label":"Cota inferior relativa adoptada","value":0.465,"unit":"m","source":"8–8","status":"interpretación con conflicto conservado"},{"label":"Cota superior relativa adoptada","value":0.515,"unit":"m","source":"8–8","status":"documentada / separación por material"}],"geometry":[{"label":"Extensión de la malla en X","value":1.0005760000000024,"unit":"m","source":"Geometría releída del IFC; datum absoluto de proceso provisional","status":"derivado"},{"label":"Extensión de la malla en Y","value":0.9151279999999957,"unit":"m","source":"Geometría releída del IFC; datum absoluto de proceso provisional","status":"derivado"},{"label":"Extensión de la malla en Z","value":0.050000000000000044,"unit":"m","source":"Geometría releída del IFC; datum absoluto de proceso provisional","status":"derivado"},{"label":"Cota inferior de visualización","value":286.565,"unit":"m","source":"Geometría releída del IFC; datum absoluto de proceso provisional","status":"derivado"},{"label":"Cota superior de visualización","value":286.615,"unit":"m","source":"Geometría releída del IFC; datum absoluto de proceso provisional","status":"derivado"}]} | ["Planta: −2,400 m. Sección 8–8: fondo −2,000 m, coronación de losa −1,400 m. Se adopta sección; pendiente de aclaración."] | {"Cota inferior relativa (m)":0.465,"Cota superior relativa (m)":0.515,"Cero absoluto de visualización (m)":286.1,"Estado del cero absoluto":"Provisional","Criterio":"Las cotas relativas proceden del dibujo; la equivalencia absoluta no está confirmada."} | F-LV1802C | ["LV1802C"] | [] | 8–8 | ["2719/25CB","2719/E3A8","1FEC2"] | F-LV1802C/Cimentación del vaporizador LV1802C · mortero de apoyo 2 | {"boundingBoxM":{"min":[47.955092,36.137362,1.565],"max":[48.955668,37.05249,1.615]},"extentsM":[1.000576,0.915128,0.05],"meshSurfaceM2":1.610001,"meshVolumeM3":0.036,"closedSolid":true,"basis":"Magnitudes de las mallas representadas, no cantidades certificadas de obra, compra o fabricación. Las partes pueden compartir superficies; no se suman como un despiece de materiales."} | {"profileId":"grout_ha35","name":"Grout HA-35 sin retracción","materialName":"Mortero HA-35 de alta resistencia sin retracción","physicalMaterialStatus":"documentado","physicalMaterialSource":"Capa superior de 50 mm expresada en las secciones del fabricante","appearanceStatus":"criterio_visual","appearanceBasis":"Interpretación visual del material documental; el acabado, tono y parámetros PBR no son una especificación contractual.","note":"La apariencia gráfica no modifica ni confirma la especificación física del material."} | {"elementId":"found_0904_ebd95b663d3032","ifcGuid":"2fDvHk0r9Qfuw$tMN7W$zZ","ifcClass":"IfcSlab","buildingId":"process_plant","buildingName":"Zona de separación de aire","sourceDocumentId":"LHD2609-JG00100-20260904","sourceRepresentationKind":"foundation"} | {"profileId":"grout_ha35","name":"Grout HA-35 sin retracción","status":"criterio_visual","basis":"Interpretación visual del material documental; el acabado, tono y parámetros PBR no son una especificación contractual.","physicalMaterialUnchanged":true} | LV1802C | 2719/25CB, 2719/E3A8, 1FEC2 | Mortero HA-35 de alta resistencia sin retracción | 0.465 | 0.515 | 0.72 | 0.036 | Sección y contornos del fabricante; incidencias conservadas | Grout HA-35 sin retracción | found_0904_ebd95b663d3032 | documentado | Capa superior de 50 mm expresada en las secciones del fabricante | 0.9 | 0.8 | grout_ha35 | [0.792157,0.776471,0.721569] | 0.94 | Planta: −2,400 m. Sección 8–8: fondo −2,000 m, coronación de losa −1,400 m. Se adopta sección; pendiente de aclaración.
Cimentación del vaporizador LV1802C · mortero de apoyo 3 | Mortero HA-35 de alta resistencia sin retracción | 1.00058 | 0.915128 | 0.05 | 286.565 | 286.615 | 1.61 | 0.036 | {"documentId":"LHD2609-JG00100-20260904","title":"Cimentaciones de equipos y pedestales del fabricante · revisión recibida 04/09/2026","date":"2026-09-04","sheet":"8–8","fileName":"LHD2609-JG00100_20260904.dwg","revisionCaveat":"Fecha de revisión tomada del nombre recibido; cajetines internos mantienen 02/07/2026 y algunos textos de plantilla.","sourceFileSha256":"b42eb027b7bc0b14c38d1d13514f4899b58a732aa8d0ba2ccf10fa2fc3192890"} | {"name":"Mortero HA-35 de alta resistencia sin retracción","status":"documentado","source":"Capa superior de 50 mm expresada en las secciones del fabricante"} | {"documented":[{"label":"Extensión local X","value":0.9,"unit":"m","source":"2719/25CB, 2719/E3A8, 1FEC2","status":"derivada del contorno CAD"},{"label":"Extensión local Y","value":0.8,"unit":"m","source":"2719/25CB, 2719/E3A8, 1FEC2","status":"derivada del contorno CAD"},{"label":"Cota inferior relativa adoptada","value":0.465,"unit":"m","source":"8–8","status":"interpretación con conflicto conservado"},{"label":"Cota superior relativa adoptada","value":0.515,"unit":"m","source":"8–8","status":"documentada / separación por material"}],"geometry":[{"label":"Extensión de la malla en X","value":1.0005760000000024,"unit":"m","source":"Geometría releída del IFC; datum absoluto de proceso provisional","status":"derivado"},{"label":"Extensión de la malla en Y","value":0.9151279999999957,"unit":"m","source":"Geometría releída del IFC; datum absoluto de proceso provisional","status":"derivado"},{"label":"Extensión de la malla en Z","value":0.050000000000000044,"unit":"m","source":"Geometría releída del IFC; datum absoluto de proceso provisional","status":"derivado"},{"label":"Cota inferior de visualización","value":286.565,"unit":"m","source":"Geometría releída del IFC; datum absoluto de proceso provisional","status":"derivado"},{"label":"Cota superior de visualización","value":286.615,"unit":"m","source":"Geometría releída del IFC; datum absoluto de proceso provisional","status":"derivado"}]} | ["Planta: −2,400 m. Sección 8–8: fondo −2,000 m, coronación de losa −1,400 m. Se adopta sección; pendiente de aclaración."] | {"Cota inferior relativa (m)":0.465,"Cota superior relativa (m)":0.515,"Cero absoluto de visualización (m)":286.1,"Estado del cero absoluto":"Provisional","Criterio":"Las cotas relativas proceden del dibujo; la equivalencia absoluta no está confirmada."} | F-LV1802C | ["LV1802C"] | [] | 8–8 | ["2719/25CB","2719/E3A8","1FEC2"] | F-LV1802C/Cimentación del vaporizador LV1802C · mortero de apoyo 3 | {"boundingBoxM":{"min":[47.686226,34.181758,1.565],"max":[48.686802,35.096886,1.615]},"extentsM":[1.000576,0.915128,0.05],"meshSurfaceM2":1.61,"meshVolumeM3":0.036,"closedSolid":true,"basis":"Magnitudes de las mallas representadas, no cantidades certificadas de obra, compra o fabricación. Las partes pueden compartir superficies; no se suman como un despiece de materiales."} | {"profileId":"grout_ha35","name":"Grout HA-35 sin retracción","materialName":"Mortero HA-35 de alta resistencia sin retracción","physicalMaterialStatus":"documentado","physicalMaterialSource":"Capa superior de 50 mm expresada en las secciones del fabricante","appearanceStatus":"criterio_visual","appearanceBasis":"Interpretación visual del material documental; el acabado, tono y parámetros PBR no son una especificación contractual.","note":"La apariencia gráfica no modifica ni confirma la especificación física del material."} | {"elementId":"found_0904_064fa9b0b0b220","ifcGuid":"3BqMmggFLTMeD$WuuCdsxs","ifcClass":"IfcSlab","buildingId":"process_plant","buildingName":"Zona de separación de aire","sourceDocumentId":"LHD2609-JG00100-20260904","sourceRepresentationKind":"foundation"} | {"profileId":"grout_ha35","name":"Grout HA-35 sin retracción","status":"criterio_visual","basis":"Interpretación visual del material documental; el acabado, tono y parámetros PBR no son una especificación contractual.","physicalMaterialUnchanged":true} | LV1802C | 2719/25CB, 2719/E3A8, 1FEC2 | Mortero HA-35 de alta resistencia sin retracción | 0.465 | 0.515 | 0.72 | 0.036 | Sección y contornos del fabricante; incidencias conservadas | Grout HA-35 sin retracción | found_0904_064fa9b0b0b220 | documentado | Capa superior de 50 mm expresada en las secciones del fabricante | 0.9 | 0.8 | grout_ha35 | [0.792157,0.776471,0.721569] | 0.94 | Planta: −2,400 m. Sección 8–8: fondo −2,000 m, coronación de losa −1,400 m. Se adopta sección; pendiente de aclaración.
Cimentación del vaporizador LV1802C · mortero de apoyo 4 | Mortero HA-35 de alta resistencia sin retracción | 1.00058 | 0.915128 | 0.05 | 286.565 | 286.615 | 1.61 | 0.036 | {"documentId":"LHD2609-JG00100-20260904","title":"Cimentaciones de equipos y pedestales del fabricante · revisión recibida 04/09/2026","date":"2026-09-04","sheet":"8–8","fileName":"LHD2609-JG00100_20260904.dwg","revisionCaveat":"Fecha de revisión tomada del nombre recibido; cajetines internos mantienen 02/07/2026 y algunos textos de plantilla.","sourceFileSha256":"b42eb027b7bc0b14c38d1d13514f4899b58a732aa8d0ba2ccf10fa2fc3192890"} | {"name":"Mortero HA-35 de alta resistencia sin retracción","status":"documentado","source":"Capa superior de 50 mm expresada en las secciones del fabricante"} | {"documented":[{"label":"Extensión local X","value":0.9,"unit":"m","source":"2719/25CB, 2719/E3A8, 1FEC2","status":"derivada del contorno CAD"},{"label":"Extensión local Y","value":0.8,"unit":"m","source":"2719/25CB, 2719/E3A8, 1FEC2","status":"derivada del contorno CAD"},{"label":"Cota inferior relativa adoptada","value":0.465,"unit":"m","source":"8–8","status":"interpretación con conflicto conservado"},{"label":"Cota superior relativa adoptada","value":0.515,"unit":"m","source":"8–8","status":"documentada / separación por material"}],"geometry":[{"label":"Extensión de la malla en X","value":1.0005760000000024,"unit":"m","source":"Geometría releída del IFC; datum absoluto de proceso provisional","status":"derivado"},{"label":"Extensión de la malla en Y","value":0.9151279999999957,"unit":"m","source":"Geometría releída del IFC; datum absoluto de proceso provisional","status":"derivado"},{"label":"Extensión de la malla en Z","value":0.050000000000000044,"unit":"m","source":"Geometría releída del IFC; datum absoluto de proceso provisional","status":"derivado"},{"label":"Cota inferior de visualización","value":286.565,"unit":"m","source":"Geometría releída del IFC; datum absoluto de proceso provisional","status":"derivado"},{"label":"Cota superior de visualización","value":286.615,"unit":"m","source":"Geometría releída del IFC; datum absoluto de proceso provisional","status":"derivado"}]} | ["Planta: −2,400 m. Sección 8–8: fondo −2,000 m, coronación de losa −1,400 m. Se adopta sección; pendiente de aclaración."] | {"Cota inferior relativa (m)":0.465,"Cota superior relativa (m)":0.515,"Cero absoluto de visualización (m)":286.1,"Estado del cero absoluto":"Provisional","Criterio":"Las cotas relativas proceden del dibujo; la equivalencia absoluta no está confirmada."} | F-LV1802C | ["LV1802C"] | [] | 8–8 | ["2719/25CB","2719/E3A8","1FEC2"] | F-LV1802C/Cimentación del vaporizador LV1802C · mortero de apoyo 4 | {"boundingBoxM":{"min":[45.171878,34.527444,1.565],"max":[46.172454,35.442572,1.615]},"extentsM":[1.000576,0.915128,0.05],"meshSurfaceM2":1.609999,"meshVolumeM3":0.036,"closedSolid":true,"basis":"Magnitudes de las mallas representadas, no cantidades certificadas de obra, compra o fabricación. Las partes pueden compartir superficies; no se suman como un despiece de materiales."} | {"profileId":"grout_ha35","name":"Grout HA-35 sin retracción","materialName":"Mortero HA-35 de alta resistencia sin retracción","physicalMaterialStatus":"documentado","physicalMaterialSource":"Capa superior de 50 mm expresada en las secciones del fabricante","appearanceStatus":"criterio_visual","appearanceBasis":"Interpretación visual del material documental; el acabado, tono y parámetros PBR no son una especificación contractual.","note":"La apariencia gráfica no modifica ni confirma la especificación física del material."} | {"elementId":"found_0904_e0a9ebf030837d","ifcGuid":"2WZ5kbhMLK2R4O$OPcxES0","ifcClass":"IfcSlab","buildingId":"process_plant","buildingName":"Zona de separación de aire","sourceDocumentId":"LHD2609-JG00100-20260904","sourceRepresentationKind":"foundation"} | {"profileId":"grout_ha35","name":"Grout HA-35 sin retracción","status":"criterio_visual","basis":"Interpretación visual del material documental; el acabado, tono y parámetros PBR no son una especificación contractual.","physicalMaterialUnchanged":true} | LV1802C | 2719/25CB, 2719/E3A8, 1FEC2 | Mortero HA-35 de alta resistencia sin retracción | 0.465 | 0.515 | 0.72 | 0.036 | Sección y contornos del fabricante; incidencias conservadas | Grout HA-35 sin retracción | found_0904_e0a9ebf030837d | documentado | Capa superior de 50 mm expresada en las secciones del fabricante | 0.9 | 0.8 | grout_ha35 | [0.792157,0.776471,0.721569] | 0.94 | Planta: −2,400 m. Sección 8–8: fondo −2,000 m, coronación de losa −1,400 m. Se adopta sección; pendiente de aclaración.
Cimentación del vaporizador LV1802C · mortero de apoyo 5 | Mortero HA-35 de alta resistencia sin retracción | 1.00058 | 0.915129 | 0.05 | 286.565 | 286.615 | 1.61 | 0.036 | {"documentId":"LHD2609-JG00100-20260904","title":"Cimentaciones de equipos y pedestales del fabricante · revisión recibida 04/09/2026","date":"2026-09-04","sheet":"8–8","fileName":"LHD2609-JG00100_20260904.dwg","revisionCaveat":"Fecha de revisión tomada del nombre recibido; cajetines internos mantienen 02/07/2026 y algunos textos de plantilla.","sourceFileSha256":"b42eb027b7bc0b14c38d1d13514f4899b58a732aa8d0ba2ccf10fa2fc3192890"} | {"name":"Mortero HA-35 de alta resistencia sin retracción","status":"documentado","source":"Capa superior de 50 mm expresada en las secciones del fabricante"} | {"documented":[{"label":"Extensión local X","value":0.9,"unit":"m","source":"2719/25CB, 2719/E3A8, 1FEC2","status":"derivada del contorno CAD"},{"label":"Extensión local Y","value":0.8,"unit":"m","source":"2719/25CB, 2719/E3A8, 1FEC2","status":"derivada del contorno CAD"},{"label":"Cota inferior relativa adoptada","value":0.465,"unit":"m","source":"8–8","status":"interpretación con conflicto conservado"},{"label":"Cota superior relativa adoptada","value":0.515,"unit":"m","source":"8–8","status":"documentada / separación por material"}],"geometry":[{"label":"Extensión de la malla en X","value":1.0005759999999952,"unit":"m","source":"Geometría releída del IFC; datum absoluto de proceso provisional","status":"derivado"},{"label":"Extensión de la malla en Y","value":0.9151290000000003,"unit":"m","source":"Geometría releída del IFC; datum absoluto de proceso provisional","status":"derivado"},{"label":"Extensión de la malla en Z","value":0.050000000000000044,"unit":"m","source":"Geometría releída del IFC; datum absoluto de proceso provisional","status":"derivado"},{"label":"Cota inferior de visualización","value":286.565,"unit":"m","source":"Geometría releída del IFC; datum absoluto de proceso provisional","status":"derivado"},{"label":"Cota superior de visualización","value":286.615,"unit":"m","source":"Geometría releída del IFC; datum absoluto de proceso provisional","status":"derivado"}]} | ["Planta: −2,400 m. Sección 8–8: fondo −2,000 m, coronación de losa −1,400 m. Se adopta sección; pendiente de aclaración."] | {"Cota inferior relativa (m)":0.465,"Cota superior relativa (m)":0.515,"Cero absoluto de visualización (m)":286.1,"Estado del cero absoluto":"Provisional","Criterio":"Las cotas relativas proceden del dibujo; la equivalencia absoluta no está confirmada."} | F-LV1802C | ["LV1802C"] | [] | 8–8 | ["2719/25CB","2719/E3A8","1FEC2"] | F-LV1802C/Cimentación del vaporizador LV1802C · mortero de apoyo 5 | {"boundingBoxM":{"min":[46.404594,35.211921,1.565],"max":[47.40517,36.12705,1.615]},"extentsM":[1.000576,0.915129,0.05],"meshSurfaceM2":1.610001,"meshVolumeM3":0.036,"closedSolid":true,"basis":"Magnitudes de las mallas representadas, no cantidades certificadas de obra, compra o fabricación. Las partes pueden compartir superficies; no se suman como un despiece de materiales."} | {"profileId":"grout_ha35","name":"Grout HA-35 sin retracción","materialName":"Mortero HA-35 de alta resistencia sin retracción","physicalMaterialStatus":"documentado","physicalMaterialSource":"Capa superior de 50 mm expresada en las secciones del fabricante","appearanceStatus":"criterio_visual","appearanceBasis":"Interpretación visual del material documental; el acabado, tono y parámetros PBR no son una especificación contractual.","note":"La apariencia gráfica no modifica ni confirma la especificación física del material."} | {"elementId":"found_0904_32c81642b7a681","ifcGuid":"1aqxVKH1HQuPO9srrzoXYi","ifcClass":"IfcSlab","buildingId":"process_plant","buildingName":"Zona de separación de aire","sourceDocumentId":"LHD2609-JG00100-20260904","sourceRepresentationKind":"foundation"} | {"profileId":"grout_ha35","name":"Grout HA-35 sin retracción","status":"criterio_visual","basis":"Interpretación visual del material documental; el acabado, tono y parámetros PBR no son una especificación contractual.","physicalMaterialUnchanged":true} | LV1802C | 2719/25CB, 2719/E3A8, 1FEC2 | Mortero HA-35 de alta resistencia sin retracción | 0.465 | 0.515 | 0.72 | 0.036 | Sección y contornos del fabricante; incidencias conservadas | Grout HA-35 sin retracción | found_0904_32c81642b7a681 | documentado | Capa superior de 50 mm expresada en las secciones del fabricante | 0.9 | 0.8 | grout_ha35 | [0.792157,0.776471,0.721569] | 0.94 | Planta: −2,400 m. Sección 8–8: fondo −2,000 m, coronación de losa −1,400 m. Se adopta sección; pendiente de aclaración.
Cimentación común de torres de refrigeración · capa de limpieza | Hormigón de limpieza HA-20 | 7.59789 | 9.9477 | 0.1 | 284 | 284.1 | 120.545 | 5.87156 | {"documentId":"LHD2609-JG00100-20260904","title":"Cimentaciones de equipos y pedestales del fabricante · revisión recibida 04/09/2026","date":"2026-09-04","sheet":"9–9 / 9A–9A","fileName":"LHD2609-JG00100_20260904.dwg","revisionCaveat":"Fecha de revisión tomada del nombre recibido; cajetines internos mantienen 02/07/2026 y algunos textos de plantilla.","sourceFileSha256":"b42eb027b7bc0b14c38d1d13514f4899b58a732aa8d0ba2ccf10fa2fc3192890"} | {"name":"Hormigón de limpieza HA-20","status":"documentado","source":"Secciones del fabricante: capa de limpieza de 100 mm; nota 2CED5"} | {"documented":[{"label":"Extensión local X","value":6.41,"unit":"m","source":"25DC/25E1, 25DC/25E2, 25DC/25E4, 25DC/2604, 25DC/25E5, 2473E","status":"derivada del contorno CAD"},{"label":"Extensión local Y","value":9.16,"unit":"m","source":"25DC/25E1, 25DC/25E2, 25DC/25E4, 25DC/2604, 25DC/25E5, 2473E","status":"derivada del contorno CAD"},{"label":"Cota inferior relativa adoptada","value":-2.1,"unit":"m","source":"9–9 / 9A–9A","status":"interpretación con conflicto conservado"},{"label":"Cota superior relativa adoptada","value":-2,"unit":"m","source":"9–9 / 9A–9A","status":"documentada / separación por material"}],"geometry":[{"label":"Extensión de la malla en X","value":7.597892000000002,"unit":"m","source":"Geometría releída del IFC; datum absoluto de proceso provisional","status":"derivado"},{"label":"Extensión de la malla en Y","value":9.947703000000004,"unit":"m","source":"Geometría releída del IFC; datum absoluto de proceso provisional","status":"derivado"},{"label":"Extensión de la malla en Z","value":0.09999999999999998,"unit":"m","source":"Geometría releída del IFC; datum absoluto de proceso provisional","status":"derivado"},{"label":"Cota inferior de visualización","value":284.0,"unit":"m","source":"Geometría releída del IFC; datum absoluto de proceso provisional","status":"derivado"},{"label":"Cota superior de visualización","value":284.1,"unit":"m","source":"Geometría releída del IFC; datum absoluto de proceso provisional","status":"derivado"}]} | ["Planta: −2,200 m. Secciones: fondo −2,000 m, losa superior −1,200 m; se adoptan secciones.","La última línea transversal presenta una discrepancia de 4 mm respecto a los ejes de pilares; se conserva la posición de cada contorno fuente."] | {"Cota inferior relativa (m)":-2.1,"Cota superior relativa (m)":-2,"Cero absoluto de visualización (m)":286.1,"Estado del cero absoluto":"Provisional","Criterio":"Las cotas relativas proceden del dibujo; la equivalencia absoluta no está confirmada."} | F-WT3001 | ["WT3001A","WT3001B","WT3001C","WT3001D"] | [] | 9–9 / 9A–9A | ["25DC/25E1","25DC/25E2","25DC/25E4","25DC/2604","25DC/25E5","2473E"] | F-WT3001/Cimentación común de torres de refrigeración · capa de limpieza | {"boundingBoxM":{"min":[35.543676,41.768837,-1.0],"max":[43.141568,51.71654,-0.9]},"extentsM":[7.597892,9.947703,0.1],"meshSurfaceM2":120.545194,"meshVolumeM3":5.87156,"closedSolid":true,"basis":"Magnitudes de las mallas representadas, no cantidades certificadas de obra, compra o fabricación. Las partes pueden compartir superficies; no se suman como un despiece de materiales."} | {"profileId":"concrete_ha20","name":"Hormigón de limpieza HA-20","materialName":"Hormigón de limpieza HA-20","physicalMaterialStatus":"documentado","physicalMaterialSource":"Secciones del fabricante: capa de limpieza de 100 mm; nota 2CED5","appearanceStatus":"criterio_visual","appearanceBasis":"Interpretación visual del material documental; el acabado, tono y parámetros PBR no son una especificación contractual.","note":"La apariencia gráfica no modifica ni confirma la especificación física del material."} | {"elementId":"found_0904_f664036c7b87c2","ifcGuid":"2JUI7s0wrUthulqTpqIPQC","ifcClass":"IfcSlab","buildingId":"process_plant","buildingName":"Zona de separación de aire","sourceDocumentId":"LHD2609-JG00100-20260904","sourceRepresentationKind":"foundation"} | {"profileId":"concrete_ha20","name":"Hormigón de limpieza HA-20","status":"criterio_visual","basis":"Interpretación visual del material documental; el acabado, tono y parámetros PBR no son una especificación contractual.","physicalMaterialUnchanged":true} | WT3001A, WT3001B, WT3001C, WT3001D | 25DC/25E1, 25DC/25E2, 25DC/25E4, 25DC/2604, 25DC/25E5, 2473E | Hormigón de limpieza HA-20 | -2.1 | -2 | 58.7156 | 5.87156 | Sección y contornos del fabricante; incidencias conservadas | Hormigón de limpieza HA-20 | found_0904_f664036c7b87c2 | documentado | Secciones del fabricante: capa de limpieza de 100 mm; nota 2CED5 | 6.41 | 9.16 | concrete_ha20 | [0.721569,0.709804,0.658824] | 0.98 | Planta: −2,200 m. Secciones: fondo −2,000 m, losa superior −1,200 m; se adoptan secciones. / La última línea transversal presenta una discrepancia de 4 mm respecto a los ejes de pilares; se conserva la posición de cada contorno fuente.
Base de bombas y dosificación · capa de limpieza | Hormigón de limpieza HA-20 | 6.60596 | 2.80353 | 0.1 | 285 | 285.1 | 26.63 | 1.248 | {"documentId":"LHD2609-JG00100-20260904","title":"Cimentaciones de equipos y pedestales del fabricante · revisión recibida 04/09/2026","date":"2026-09-04","sheet":"10–10","fileName":"LHD2609-JG00100_20260904.dwg","revisionCaveat":"Fecha de revisión tomada del nombre recibido; cajetines internos mantienen 02/07/2026 y algunos textos de plantilla.","sourceFileSha256":"b42eb027b7bc0b14c38d1d13514f4899b58a732aa8d0ba2ccf10fa2fc3192890"} | {"name":"Hormigón de limpieza HA-20","status":"documentado","source":"Secciones del fabricante: capa de limpieza de 100 mm; nota 2CED5"} | {"documented":[{"label":"Extensión local X","value":6.4,"unit":"m","source":"26B8/26BE, 24851","status":"derivada del contorno CAD"},{"label":"Extensión local Y","value":1.95,"unit":"m","source":"26B8/26BE, 24851","status":"derivada del contorno CAD"},{"label":"Cota inferior relativa adoptada","value":-1.1,"unit":"m","source":"10–10","status":"documentada"},{"label":"Cota superior relativa adoptada","value":-1,"unit":"m","source":"10–10","status":"documentada / separación por material"}],"geometry":[{"label":"Extensión de la malla en X","value":6.605955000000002,"unit":"m","source":"Geometría releída del IFC; datum absoluto de proceso provisional","status":"derivado"},{"label":"Extensión de la malla en Y","value":2.8035330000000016,"unit":"m","source":"Geometría releída del IFC; datum absoluto de proceso provisional","status":"derivado"},{"label":"Extensión de la malla en Z","value":0.1,"unit":"m","source":"Geometría releída del IFC; datum absoluto de proceso provisional","status":"derivado"},{"label":"Cota inferior de visualización","value":285.0,"unit":"m","source":"Geometría releída del IFC; datum absoluto de proceso provisional","status":"derivado"},{"label":"Cota superior de visualización","value":285.1,"unit":"m","source":"Geometría releída del IFC; datum absoluto de proceso provisional","status":"derivado"}]} | [] | {"Cota inferior relativa (m)":-1.1,"Cota superior relativa (m)":-1,"Cero absoluto de visualización (m)":286.1,"Estado del cero absoluto":"Provisional","Criterio":"Las cotas relativas proceden del dibujo; la equivalencia absoluta no está confirmada."} | F-SKID | ["PUMPS-DOSING-PLAN"] | [] | 10–10 | ["26B8/26BE","24851"] | F-SKID/Base de bombas y dosificación · capa de limpieza | {"boundingBoxM":{"min":[36.311935,55.397554,0.0],"max":[42.91789,58.201087,0.1]},"extentsM":[6.605955,2.803533,0.1],"meshSurfaceM2":26.63,"meshVolumeM3":1.248,"closedSolid":true,"basis":"Magnitudes de las mallas representadas, no cantidades certificadas de obra, compra o fabricación. Las partes pueden compartir superficies; no se suman como un despiece de materiales."} | {"profileId":"concrete_ha20","name":"Hormigón de limpieza HA-20","materialName":"Hormigón de limpieza HA-20","physicalMaterialStatus":"documentado","physicalMaterialSource":"Secciones del fabricante: capa de limpieza de 100 mm; nota 2CED5","appearanceStatus":"criterio_visual","appearanceBasis":"Interpretación visual del material documental; el acabado, tono y parámetros PBR no son una especificación contractual.","note":"La apariencia gráfica no modifica ni confirma la especificación física del material."} | {"elementId":"found_0904_9fc68ac0a59c86","ifcGuid":"1nAJRYpyzQde8heW9zx9L9","ifcClass":"IfcSlab","buildingId":"process_plant","buildingName":"Zona de separación de aire","sourceDocumentId":"LHD2609-JG00100-20260904","sourceRepresentationKind":"foundation"} | {"profileId":"concrete_ha20","name":"Hormigón de limpieza HA-20","status":"criterio_visual","basis":"Interpretación visual del material documental; el acabado, tono y parámetros PBR no son una especificación contractual.","physicalMaterialUnchanged":true} | PUMPS-DOSING-PLAN | 26B8/26BE, 24851 | Hormigón de limpieza HA-20 | -1.1 | -1 | 12.48 | 1.248 | Contornos y sección documentados por el fabricante | Hormigón de limpieza HA-20 | found_0904_9fc68ac0a59c86 | documentado | Secciones del fabricante: capa de limpieza de 100 mm; nota 2CED5 | 6.4 | 1.95 | concrete_ha20 | [0.721569,0.709804,0.658824] | 0.98
Base de bombas y dosificación · mortero superior de 50 mm | Mortero HA-35 de alta resistencia sin retracción | 6.38058 | 2.57816 | 0.05 | 286.25 | 286.3 | 22.495 | 0.5425 | {"documentId":"LHD2609-JG00100-20260904","title":"Cimentaciones de equipos y pedestales del fabricante · revisión recibida 04/09/2026","date":"2026-09-04","sheet":"10–10","fileName":"LHD2609-JG00100_20260904.dwg","revisionCaveat":"Fecha de revisión tomada del nombre recibido; cajetines internos mantienen 02/07/2026 y algunos textos de plantilla.","sourceFileSha256":"b42eb027b7bc0b14c38d1d13514f4899b58a732aa8d0ba2ccf10fa2fc3192890"} | {"name":"Mortero HA-35 de alta resistencia sin retracción","status":"documentado","source":"Capa superior de 50 mm expresada en las secciones del fabricante"} | {"documented":[{"label":"Extensión local X","value":6.2,"unit":"m","source":"26B8/26BE, 24851","status":"derivada del contorno CAD"},{"label":"Extensión local Y","value":1.75,"unit":"m","source":"26B8/26BE, 24851","status":"derivada del contorno CAD"},{"label":"Cota inferior relativa adoptada","value":0.15000000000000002,"unit":"m","source":"10–10","status":"documentada"},{"label":"Cota superior relativa adoptada","value":0.2,"unit":"m","source":"10–10","status":"documentada / separación por material"}],"geometry":[{"label":"Extensión de la malla en X","value":6.380578,"unit":"m","source":"Geometría releída del IFC; datum absoluto de proceso provisional","status":"derivado"},{"label":"Extensión de la malla en Y","value":2.578156,"unit":"m","source":"Geometría releída del IFC; datum absoluto de proceso provisional","status":"derivado"},{"label":"Extensión de la malla en Z","value":0.050000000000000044,"unit":"m","source":"Geometría releída del IFC; datum absoluto de proceso provisional","status":"derivado"},{"label":"Cota inferior de visualización","value":286.25,"unit":"m","source":"Geometría releída del IFC; datum absoluto de proceso provisional","status":"derivado"},{"label":"Cota superior de visualización","value":286.3,"unit":"m","source":"Geometría releída del IFC; datum absoluto de proceso provisional","status":"derivado"}]} | [] | {"Cota inferior relativa (m)":0.15000000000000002,"Cota superior relativa (m)":0.2,"Cero absoluto de visualización (m)":286.1,"Estado del cero absoluto":"Provisional","Criterio":"Las cotas relativas proceden del dibujo; la equivalencia absoluta no está confirmada."} | F-SKID | ["PUMPS-DOSING-PLAN"] | [] | 10–10 | ["26B8/26BE","24851"] | F-SKID/Base de bombas y dosificación · mortero superior de 50 mm | {"boundingBoxM":{"min":[36.424623,55.510243,1.25],"max":[42.805201,58.088399,1.3]},"extentsM":[6.380578,2.578156,0.05],"meshSurfaceM2":22.495001,"meshVolumeM3":0.5425,"closedSolid":true,"basis":"Magnitudes de las mallas representadas, no cantidades certificadas de obra, compra o fabricación. Las partes pueden compartir superficies; no se suman como un despiece de materiales."} | {"profileId":"grout_ha35","name":"Grout HA-35 sin retracción","materialName":"Mortero HA-35 de alta resistencia sin retracción","physicalMaterialStatus":"documentado","physicalMaterialSource":"Capa superior de 50 mm expresada en las secciones del fabricante","appearanceStatus":"criterio_visual","appearanceBasis":"Interpretación visual del material documental; el acabado, tono y parámetros PBR no son una especificación contractual.","note":"La apariencia gráfica no modifica ni confirma la especificación física del material."} | {"elementId":"found_0904_b8078a859dac4b","ifcGuid":"1bIcOrBrPOUgU0wNJcHRTx","ifcClass":"IfcSlab","buildingId":"process_plant","buildingName":"Zona de separación de aire","sourceDocumentId":"LHD2609-JG00100-20260904","sourceRepresentationKind":"foundation"} | {"profileId":"grout_ha35","name":"Grout HA-35 sin retracción","status":"criterio_visual","basis":"Interpretación visual del material documental; el acabado, tono y parámetros PBR no son una especificación contractual.","physicalMaterialUnchanged":true} | PUMPS-DOSING-PLAN | 26B8/26BE, 24851 | Mortero HA-35 de alta resistencia sin retracción | 0.15 | 0.2 | 10.85 | 0.5425 | Contornos y sección documentados por el fabricante | Grout HA-35 sin retracción | found_0904_b8078a859dac4b | documentado | Capa superior de 50 mm expresada en las secciones del fabricante | 6.2 | 1.75 | grout_ha35 | [0.792157,0.776471,0.721569] | 0.94
Base de la caseta de analizadores · capa de limpieza | Hormigón de limpieza HA-20 | 4.56947 | 3.5441 | 0.1 | 285 | 285.1 | 26.64 | 1.26 | {"documentId":"LHD2609-JG00100-20260904","title":"Cimentaciones de equipos y pedestales del fabricante · revisión recibida 04/09/2026","date":"2026-09-04","sheet":"20–20","fileName":"LHD2609-JG00100_20260904.dwg","revisionCaveat":"Fecha de revisión tomada del nombre recibido; cajetines internos mantienen 02/07/2026 y algunos textos de plantilla.","sourceFileSha256":"b42eb027b7bc0b14c38d1d13514f4899b58a732aa8d0ba2ccf10fa2fc3192890"} | {"name":"Hormigón de limpieza HA-20","status":"documentado","source":"Secciones del fabricante: capa de limpieza de 100 mm; nota 2CED5"} | {"documented":[{"label":"Extensión local X","value":4.2,"unit":"m","source":"26CA, 24873","status":"derivada del contorno CAD"},{"label":"Extensión local Y","value":3.0,"unit":"m","source":"26CA, 24873","status":"derivada del contorno CAD"},{"label":"Cota inferior relativa adoptada","value":-1.1,"unit":"m","source":"20–20","status":"documentada"},{"label":"Cota superior relativa adoptada","value":-1,"unit":"m","source":"20–20","status":"documentada / separación por material"}],"geometry":[{"label":"Extensión de la malla en X","value":4.5694719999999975,"unit":"m","source":"Geometría releída del IFC; datum absoluto de proceso provisional","status":"derivado"},{"label":"Extensión de la malla en Y","value":3.5440990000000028,"unit":"m","source":"Geometría releída del IFC; datum absoluto de proceso provisional","status":"derivado"},{"label":"Extensión de la malla en Z","value":0.1,"unit":"m","source":"Geometría releída del IFC; datum absoluto de proceso provisional","status":"derivado"},{"label":"Cota inferior de visualización","value":285.0,"unit":"m","source":"Geometría releída del IFC; datum absoluto de proceso provisional","status":"derivado"},{"label":"Cota superior de visualización","value":285.1,"unit":"m","source":"Geometría releída del IFC; datum absoluto de proceso provisional","status":"derivado"}]} | [] | {"Cota inferior relativa (m)":-1.1,"Cota superior relativa (m)":-1,"Cero absoluto de visualización (m)":286.1,"Estado del cero absoluto":"Provisional","Criterio":"Las cotas relativas proceden del dibujo; la equivalencia absoluta no está confirmada."} | F-ANALYSIS | ["ANALYSIS-CABIN"] | [] | 20–20 | ["26CA","24873"] | F-ANALYSIS/Base de la caseta de analizadores · capa de limpieza | {"boundingBoxM":{"min":[43.284391,38.865671,0.0],"max":[47.853863,42.40977,0.1]},"extentsM":[4.569472,3.544099,0.1],"meshSurfaceM2":26.640004,"meshVolumeM3":1.26,"closedSolid":true,"basis":"Magnitudes de las mallas representadas, no cantidades certificadas de obra, compra o fabricación. Las partes pueden compartir superficies; no se suman como un despiece de materiales."} | {"profileId":"concrete_ha20","name":"Hormigón de limpieza HA-20","materialName":"Hormigón de limpieza HA-20","physicalMaterialStatus":"documentado","physicalMaterialSource":"Secciones del fabricante: capa de limpieza de 100 mm; nota 2CED5","appearanceStatus":"criterio_visual","appearanceBasis":"Interpretación visual del material documental; el acabado, tono y parámetros PBR no son una especificación contractual.","note":"La apariencia gráfica no modifica ni confirma la especificación física del material."} | {"elementId":"found_0904_a9c892c36ff3b0","ifcGuid":"31HJ$J07LH3AIfN$xjXMc$","ifcClass":"IfcSlab","buildingId":"process_plant","buildingName":"Zona de separación de aire","sourceDocumentId":"LHD2609-JG00100-20260904","sourceRepresentationKind":"foundation"} | {"profileId":"concrete_ha20","name":"Hormigón de limpieza HA-20","status":"criterio_visual","basis":"Interpretación visual del material documental; el acabado, tono y parámetros PBR no son una especificación contractual.","physicalMaterialUnchanged":true} | ANALYSIS-CABIN | 26CA, 24873 | Hormigón de limpieza HA-20 | -1.1 | -1 | 12.6 | 1.26 | Contornos y sección documentados por el fabricante | Hormigón de limpieza HA-20 | found_0904_a9c892c36ff3b0 | documentado | Secciones del fabricante: capa de limpieza de 100 mm; nota 2CED5 | 4.2 | 3 | concrete_ha20 | [0.721569,0.709804,0.658824] | 0.98
Cimentación y plataforma del módulo LV-CONTAINER · capa de limpieza | Hormigón de limpieza HA-20 | 6.30366 | 12.0927 | 0.1 | 285 | 285.1 | 113.567 | 5.51513 | {"documentId":"LHD2609-JG00100-20260904","title":"Cimentaciones de equipos y pedestales del fabricante · revisión recibida 04/09/2026","date":"2026-09-04","sheet":"13–13","fileName":"LHD2609-JG00100_20260904.dwg","revisionCaveat":"Fecha de revisión tomada del nombre recibido; cajetines internos mantienen 02/07/2026 y algunos textos de plantilla.","sourceFileSha256":"b42eb027b7bc0b14c38d1d13514f4899b58a732aa8d0ba2ccf10fa2fc3192890"} | {"name":"Hormigón de limpieza HA-20","status":"documentado","source":"Secciones del fabricante: capa de limpieza de 100 mm; nota 2CED5"} | {"documented":[{"label":"Extensión local X","value":4.775,"unit":"m","source":"55EB/55F1, 1DB82, 1DE55","status":"derivada del contorno CAD"},{"label":"Extensión local Y","value":11.55,"unit":"m","source":"55EB/55F1, 1DB82, 1DE55","status":"derivada del contorno CAD"},{"label":"Cota inferior relativa adoptada","value":-1.1,"unit":"m","source":"13–13","status":"interpretación con conflicto conservado"},{"label":"Cota superior relativa adoptada","value":-1,"unit":"m","source":"13–13","status":"documentada / separación por material"}],"geometry":[{"label":"Extensión de la malla en X","value":6.303655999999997,"unit":"m","source":"Geometría releída del IFC; datum absoluto de proceso provisional","status":"derivado"},{"label":"Extensión de la malla en Y","value":12.092737,"unit":"m","source":"Geometría releída del IFC; datum absoluto de proceso provisional","status":"derivado"},{"label":"Extensión de la malla en Z","value":0.1,"unit":"m","source":"Geometría releída del IFC; datum absoluto de proceso provisional","status":"derivado"},{"label":"Cota inferior de visualización","value":285.0,"unit":"m","source":"Geometría releída del IFC; datum absoluto de proceso provisional","status":"derivado"},{"label":"Cota superior de visualización","value":285.1,"unit":"m","source":"Geometría releída del IFC; datum absoluto de proceso provisional","status":"derivado"}]} | ["La planta general y algunos croquis de apoyo muestran dimensiones transversales distintas. Se usan el contorno de cimentación y los centros de pilares de la implantación general; sección de viga VC1 400 × 400 mm y vuelo a 1050 mm del eje según detalle.","La capa de mortero sobre la losa no tiene una referencia vertical inequívoca; no se duplica una capa independiente en esa losa."] | {"Cota inferior relativa (m)":-1.1,"Cota superior relativa (m)":-1,"Cero absoluto de visualización (m)":286.1,"Estado del cero absoluto":"Provisional","Criterio":"Las cotas relativas proceden del dibujo; la equivalencia absoluta no está confirmada."} | F-LV-CONTAINER | ["LV-CONTAINER"] | [] | 13–13 | ["55EB/55F1","1DB82","1DE55"] | F-LV-CONTAINER/Cimentación y plataforma del módulo LV-CONTAINER · capa de limpieza | {"boundingBoxM":{"min":[38.313172,72.377486,0.0],"max":[44.616828,84.470223,0.1]},"extentsM":[6.303656,12.092737,0.1],"meshSurfaceM2":113.567497,"meshVolumeM3":5.515125,"closedSolid":true,"basis":"Magnitudes de las mallas representadas, no cantidades certificadas de obra, compra o fabricación. Las partes pueden compartir superficies; no se suman como un despiece de materiales."} | {"profileId":"concrete_ha20","name":"Hormigón de limpieza HA-20","materialName":"Hormigón de limpieza HA-20","physicalMaterialStatus":"documentado","physicalMaterialSource":"Secciones del fabricante: capa de limpieza de 100 mm; nota 2CED5","appearanceStatus":"criterio_visual","appearanceBasis":"Interpretación visual del material documental; el acabado, tono y parámetros PBR no son una especificación contractual.","note":"La apariencia gráfica no modifica ni confirma la especificación física del material."} | {"elementId":"found_0904_ea077e07e4c91b","ifcGuid":"3WIGgrbWXGWRysMqpcj46k","ifcClass":"IfcSlab","buildingId":"process_plant","buildingName":"Zona de separación de aire","sourceDocumentId":"LHD2609-JG00100-20260904","sourceRepresentationKind":"foundation"} | {"profileId":"concrete_ha20","name":"Hormigón de limpieza HA-20","status":"criterio_visual","basis":"Interpretación visual del material documental; el acabado, tono y parámetros PBR no son una especificación contractual.","physicalMaterialUnchanged":true} | LV-CONTAINER | 55EB/55F1, 1DB82, 1DE55 | Hormigón de limpieza HA-20 | -1.1 | -1 | 55.1512 | 5.51513 | Sección y contornos del fabricante; incidencias conservadas | Hormigón de limpieza HA-20 | found_0904_ea077e07e4c91b | documentado | Secciones del fabricante: capa de limpieza de 100 mm; nota 2CED5 | 4.775 | 11.55 | concrete_ha20 | [0.721569,0.709804,0.658824] | 0.98 | La planta general y algunos croquis de apoyo muestran dimensiones transversales distintas. Se usan el contorno de cimentación y los centros de pilares de la implantación general; sección de viga VC1 400 × 400 mm y vuelo a 1050 mm del eje según detalle. / La capa de mortero sobre la losa no tiene una referencia vertical inequívoca; no se duplica una capa independiente en esa losa.
Cimentación y plataforma del módulo LV-CONTAINER · plataforma perimetral de 120 mm |  | 6.4467 | 11.189 | 0.12 | 287.48 | 287.6 | 72.062 | 3.945 | {"documentId":"LHD2609-JG00100-20260904","title":"Cimentaciones de equipos y pedestales del fabricante · revisión recibida 04/09/2026","date":"2026-09-04","sheet":"13–13","fileName":"LHD2609-JG00100_20260904.dwg","revisionCaveat":"Fecha de revisión tomada del nombre recibido; cajetines internos mantienen 02/07/2026 y algunos textos de plantilla.","sourceFileSha256":"b42eb027b7bc0b14c38d1d13514f4899b58a732aa8d0ba2ccf10fa2fc3192890"} | {"name":"Hormigón armado · clase pendiente de confirmar","status":"Clase no confirmada en la hoja de equipo","source":"Geometría de cimentación del fabricante; no se extrapola HA-30 de la nota de pedestales."} | {"documented":[{"label":"Extensión local X","value":5.05,"unit":"m","source":"55EB/55F1, 1DB82, 1DE55","status":"derivada del contorno CAD"},{"label":"Extensión local Y","value":10.6,"unit":"m","source":"55EB/55F1, 1DB82, 1DE55","status":"derivada del contorno CAD"},{"label":"Cota inferior relativa adoptada","value":1.38,"unit":"m","source":"13–13","status":"interpretación con conflicto conservado"},{"label":"Cota superior relativa adoptada","value":1.5,"unit":"m","source":"13–13","status":"documentada / separación por material"}],"geometry":[{"label":"Extensión de la malla en X","value":6.4467,"unit":"m","source":"Geometría releída del IFC; datum absoluto de proceso provisional","status":"derivado"},{"label":"Extensión de la malla en Y","value":11.18904599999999,"unit":"m","source":"Geometría releída del IFC; datum absoluto de proceso provisional","status":"derivado"},{"label":"Extensión de la malla en Z","value":0.1200000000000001,"unit":"m","source":"Geometría releída del IFC; datum absoluto de proceso provisional","status":"derivado"},{"label":"Cota inferior de visualización","value":287.48,"unit":"m","source":"Geometría releída del IFC; datum absoluto de proceso provisional","status":"derivado"},{"label":"Cota superior de visualización","value":287.6,"unit":"m","source":"Geometría releída del IFC; datum absoluto de proceso provisional","status":"derivado"}]} | ["La planta general y algunos croquis de apoyo muestran dimensiones transversales distintas. Se usan el contorno de cimentación y los centros de pilares de la implantación general; sección de viga VC1 400 × 400 mm y vuelo a 1050 mm del eje según detalle.","La capa de mortero sobre la losa no tiene una referencia vertical inequívoca; no se duplica una capa independiente en esa losa."] | {"Cota inferior relativa (m)":1.38,"Cota superior relativa (m)":1.5,"Cero absoluto de visualización (m)":286.1,"Estado del cero absoluto":"Provisional","Criterio":"Las cotas relativas proceden del dibujo; la equivalencia absoluta no está confirmada."} | F-LV-CONTAINER | ["LV-CONTAINER"] | [] | 13–13 | ["55EB/55F1","1DB82","1DE55"] | F-LV-CONTAINER/Cimentación y plataforma del módulo LV-CONTAINER · plataforma perimetral de 120 mm | {"boundingBoxM":{"min":[38.425249,71.870388,2.48],"max":[44.871949,83.059434,2.6]},"extentsM":[6.4467,11.189046,0.12],"meshSurfaceM2":72.061995,"meshVolumeM3":3.945,"closedSolid":true,"basis":"Magnitudes de las mallas representadas, no cantidades certificadas de obra, compra o fabricación. Las partes pueden compartir superficies; no se suman como un despiece de materiales."} | {"profileId":"concrete_reinforced","name":"Hormigón armado · gris natural","materialName":"Hormigón armado · clase pendiente de confirmar","physicalMaterialStatus":"Clase no confirmada en la hoja de equipo","physicalMaterialSource":"Geometría de cimentación del fabricante; no se extrapola HA-30 de la nota de pedestales.","appearanceStatus":"criterio_visual","appearanceBasis":"Interpretación visual del material documental; el acabado, tono y parámetros PBR no son una especificación contractual.","note":"La apariencia gráfica no modifica ni confirma la especificación física del material."} | {"elementId":"found_0904_dd36a5bcfb9508","ifcGuid":"2tiR2dTsrOvgKFeNQPXtWf","ifcClass":"IfcSlab","buildingId":"process_plant","buildingName":"Zona de separación de aire","sourceDocumentId":"LHD2609-JG00100-20260904","sourceRepresentationKind":"foundation"} | {"profileId":"concrete_reinforced","name":"Hormigón armado · gris natural","status":"criterio_visual","basis":"Interpretación visual del material documental; el acabado, tono y parámetros PBR no son una especificación contractual.","physicalMaterialUnchanged":true} | LV-CONTAINER | 55EB/55F1, 1DB82, 1DE55 | Hormigón armado · clase pendiente de confirmar | 1.38 | 1.5 | 32.875 | 3.945 | Sección y contornos del fabricante; incidencias conservadas | Hormigón armado · gris natural | found_0904_dd36a5bcfb9508 | Clase no confirmada en la hoja de equipo | Geometría de cimentación del fabricante; no se extrapola HA-30 de la nota de pedestales. | 5.05 | 10.6 | concrete_reinforced | [0.666667,0.662745,0.619608] | 0.96 | La planta general y algunos croquis de apoyo muestran dimensiones transversales distintas. Se usan el contorno de cimentación y los centros de pilares de la implantación general; sección de viga VC1 400 × 400 mm y vuelo a 1050 mm del eje según detalle. / La capa de mortero sobre la losa no tiene una referencia vertical inequívoca; no se duplica una capa independiente en esa losa.
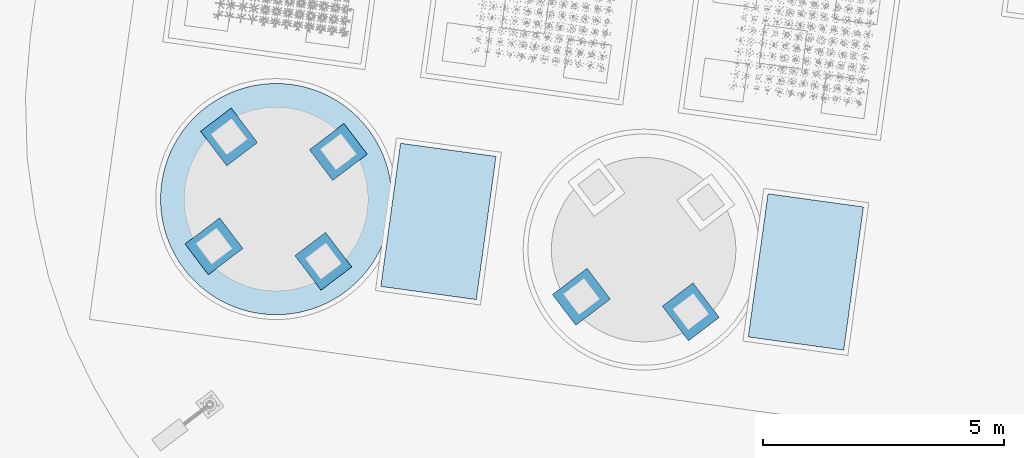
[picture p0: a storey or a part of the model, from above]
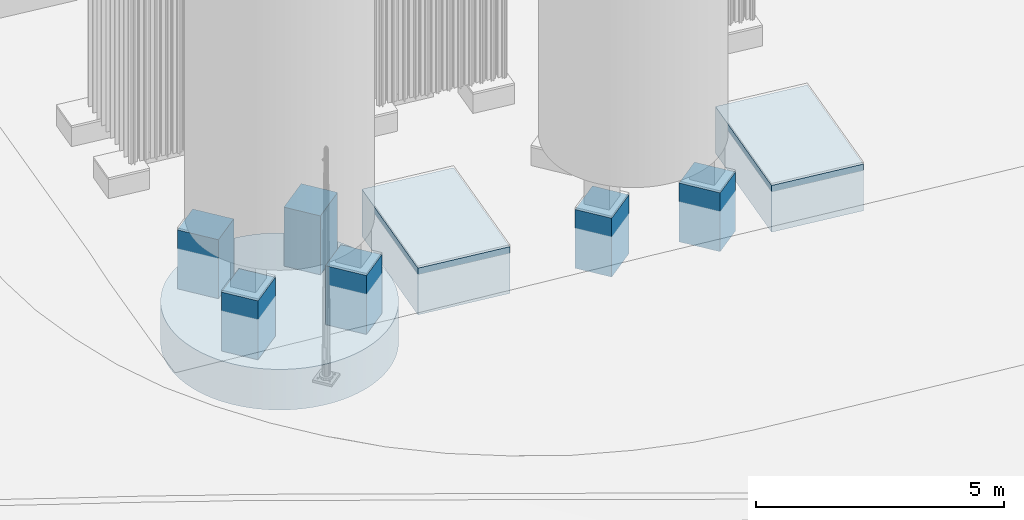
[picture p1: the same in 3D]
Properties of the parts of a building model (IFC4), part 107 of 134

# IfcSlab: Cimentación industrial (108)
Name | Material | Extensión de la malla en X (m) = ExtensionX (m) | Extensión de la malla en Y (m) = ExtensionY (m) | Extensión de la malla en Z (m) = ExtensionZ (m) = Espesor o altura real de sección (m) | Cota inferior de visualización (m) | Cota superior de visualización (m) | SuperficieDeLaMalla (m2) | VolumenGeometrico (m3) | JH_InformacionBIM, source = DocumentoFuente | material | dimensions | issues = IncidenciasPendientes | positioning = PosicionYEstado | assemblyId = Conjunto de cimentación | equipmentIds | supportPositionIds | sectionRef = Sección de referencia | sourceCadHandles | stableElementKey | geometryMetrics | materialAppearance | visualizationIdentity | appearance | Equipos asociados | Identificadores CAD de referencia | JH_Trazabilidad, Material = name | Cota inferior relativa (m) = Cota inferior relativa adoptada (m) | Cota superior relativa (m) = Cota superior relativa adoptada (m) | Área de planta (m²) | Volumen geométrico (m³) | Estado de la geometría | Acabado de visualización = Acabado | Identificador | status | JH_EvidenciaDeMaterial, source | Extensión local X (m) | Extensión local Y (m) | Perfil | ColorRGB | Rugosidad | Incidencias de origen
Cimentación y plataforma del módulo HV-CONTAINER · capa de limpieza | Hormigón de limpieza HA-20 | 12.6624 | 6.38197 | 0.1 | 285 | 285.1 | 119.174 | 5.78969 | {"documentId":"LHD2609-JG00100-20260904","title":"Cimentaciones de equipos y pedestales del fabricante · revisión recibida 04/09/2026","date":"2026-09-04","sheet":"14–14","fileName":"LHD2609-JG00100_20260904.dwg","revisionCaveat":"Fecha de revisión tomada del nombre recibido; cajetines internos mantienen 02/07/2026 y algunos textos de plantilla.","sourceFileSha256":"b42eb027b7bc0b14c38d1d13514f4899b58a732aa8d0ba2ccf10fa2fc3192890"} | {"name":"Hormigón de limpieza HA-20","status":"documentado","source":"Secciones del fabricante: capa de limpieza de 100 mm; nota 2CED5"} | {"documented":[{"label":"Extensión local X","value":12.125,"unit":"m","source":"553E/5544, 1DB82, 1DE55","status":"derivada del contorno CAD"},{"label":"Extensión local Y","value":4.775,"unit":"m","source":"553E/5544, 1DB82, 1DE55","status":"derivada del contorno CAD"},{"label":"Cota inferior relativa adoptada","value":-1.1,"unit":"m","source":"14–14","status":"interpretación con conflicto conservado"},{"label":"Cota superior relativa adoptada","value":-1,"unit":"m","source":"14–14","status":"documentada / separación por material"}],"geometry":[{"label":"Extensión de la malla en X","value":12.662379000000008,"unit":"m","source":"Geometría releída del IFC; datum absoluto de proceso provisional","status":"derivado"},{"label":"Extensión de la malla en Y","value":6.381974,"unit":"m","source":"Geometría releída del IFC; datum absoluto de proceso provisional","status":"derivado"},{"label":"Extensión de la malla en Z","value":0.1,"unit":"m","source":"Geometría releída del IFC; datum absoluto de proceso provisional","status":"derivado"},{"label":"Cota inferior de visualización","value":285.0,"unit":"m","source":"Geometría releída del IFC; datum absoluto de proceso provisional","status":"derivado"},{"label":"Cota superior de visualización","value":285.1,"unit":"m","source":"Geometría releída del IFC; datum absoluto de proceso provisional","status":"derivado"}]} | ["La planta general y algunos croquis de apoyo muestran dimensiones transversales distintas. Se usan el contorno de cimentación y los centros de pilares de la implantación general; sección de viga VC1 400 × 400 mm y vuelo a 1050 mm del eje según detalle.","La capa de mortero sobre la losa no tiene una referencia vertical inequívoca; no se duplica una capa independiente en esa losa."] | {"Cota inferior relativa (m)":-1.1,"Cota superior relativa (m)":-1,"Cero absoluto de visualización (m)":286.1,"Estado del cero absoluto":"Provisional","Criterio":"Las cotas relativas proceden del dibujo; la equivalencia absoluta no está confirmada."} | F-HV-CONTAINER | ["HV-CONTAINER"] | [] | 14–14 | ["553E/5544","1DB82","1DE55"] | F-HV-CONTAINER/Cimentación y plataforma del módulo HV-CONTAINER · capa de limpieza | {"boundingBoxM":{"min":[54.463305,78.164939,0.0],"max":[67.125684,84.546913,0.1]},"extentsM":[12.662379,6.381974,0.1],"meshSurfaceM2":119.173754,"meshVolumeM3":5.789688,"closedSolid":true,"basis":"Magnitudes de las mallas representadas, no cantidades certificadas de obra, compra o fabricación. Las partes pueden compartir superficies; no se suman como un despiece de materiales."} | {"profileId":"concrete_ha20","name":"Hormigón de limpieza HA-20","materialName":"Hormigón de limpieza HA-20","physicalMaterialStatus":"documentado","physicalMaterialSource":"Secciones del fabricante: capa de limpieza de 100 mm; nota 2CED5","appearanceStatus":"criterio_visual","appearanceBasis":"Interpretación visual del material documental; el acabado, tono y parámetros PBR no son una especificación contractual.","note":"La apariencia gráfica no modifica ni confirma la especificación física del material."} | {"elementId":"found_0904_f0afc95ba236c4","ifcGuid":"0fhd1CIZrTkwN_6M8Ck1Ty","ifcClass":"IfcSlab","buildingId":"process_plant","buildingName":"Zona de separación de aire","sourceDocumentId":"LHD2609-JG00100-20260904","sourceRepresentationKind":"foundation"} | {"profileId":"concrete_ha20","name":"Hormigón de limpieza HA-20","status":"criterio_visual","basis":"Interpretación visual del material documental; el acabado, tono y parámetros PBR no son una especificación contractual.","physicalMaterialUnchanged":true} | HV-CONTAINER | 553E/5544, 1DB82, 1DE55 | Hormigón de limpieza HA-20 | -1.1 | -1 | 57.8969 | 5.78969 | Sección y contornos del fabricante; incidencias conservadas | Hormigón de limpieza HA-20 | found_0904_f0afc95ba236c4 | documentado | Secciones del fabricante: capa de limpieza de 100 mm; nota 2CED5 | 12.125 | 4.775 | concrete_ha20 | [0.721569,0.709804,0.658824] | 0.98 | La planta general y algunos croquis de apoyo muestran dimensiones transversales distintas. Se usan el contorno de cimentación y los centros de pilares de la implantación general; sección de viga VC1 400 × 400 mm y vuelo a 1050 mm del eje según detalle. / La capa de mortero sobre la losa no tiene una referencia vertical inequívoca; no se duplica una capa independiente en esa losa.
Cimentación y plataforma del módulo HV-CONTAINER · plataforma perimetral de 120 mm |  | 11.9321 | 6.54885 | 0.12 | 287.48 | 287.6 | 76.172 | 4.17 | {"documentId":"LHD2609-JG00100-20260904","title":"Cimentaciones de equipos y pedestales del fabricante · revisión recibida 04/09/2026","date":"2026-09-04","sheet":"14–14","fileName":"LHD2609-JG00100_20260904.dwg","revisionCaveat":"Fecha de revisión tomada del nombre recibido; cajetines internos mantienen 02/07/2026 y algunos textos de plantilla.","sourceFileSha256":"b42eb027b7bc0b14c38d1d13514f4899b58a732aa8d0ba2ccf10fa2fc3192890"} | {"name":"Hormigón armado · clase pendiente de confirmar","status":"Clase no confirmada en la hoja de equipo","source":"Geometría de cimentación del fabricante; no se extrapola HA-30 de la nota de pedestales."} | {"documented":[{"label":"Extensión local X","value":11.35,"unit":"m","source":"553E/5544, 1DB82, 1DE55","status":"derivada del contorno CAD"},{"label":"Extensión local Y","value":5.05,"unit":"m","source":"553E/5544, 1DB82, 1DE55","status":"derivada del contorno CAD"},{"label":"Cota inferior relativa adoptada","value":1.38,"unit":"m","source":"14–14","status":"interpretación con conflicto conservado"},{"label":"Cota superior relativa adoptada","value":1.5,"unit":"m","source":"14–14","status":"documentada / separación por material"}],"geometry":[{"label":"Extensión de la malla en X","value":11.932057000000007,"unit":"m","source":"Geometría releída del IFC; datum absoluto de proceso provisional","status":"derivado"},{"label":"Extensión de la malla en Y","value":6.548852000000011,"unit":"m","source":"Geometría releída del IFC; datum absoluto de proceso provisional","status":"derivado"},{"label":"Extensión de la malla en Z","value":0.1200000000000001,"unit":"m","source":"Geometría releída del IFC; datum absoluto de proceso provisional","status":"derivado"},{"label":"Cota inferior de visualización","value":287.48,"unit":"m","source":"Geometría releída del IFC; datum absoluto de proceso provisional","status":"derivado"},{"label":"Cota superior de visualización","value":287.6,"unit":"m","source":"Geometría releída del IFC; datum absoluto de proceso provisional","status":"derivado"}]} | ["La planta general y algunos croquis de apoyo muestran dimensiones transversales distintas. Se usan el contorno de cimentación y los centros de pilares de la implantación general; sección de viga VC1 400 × 400 mm y vuelo a 1050 mm del eje según detalle.","La capa de mortero sobre la losa no tiene una referencia vertical inequívoca; no se duplica una capa independiente en esa losa."] | {"Cota inferior relativa (m)":1.38,"Cota superior relativa (m)":1.5,"Cero absoluto de visualización (m)":286.1,"Estado del cero absoluto":"Provisional","Criterio":"Las cotas relativas proceden del dibujo; la equivalencia absoluta no está confirmada."} | F-HV-CONTAINER | ["HV-CONTAINER"] | [] | 14–14 | ["553E/5544","1DB82","1DE55"] | F-HV-CONTAINER/Cimentación y plataforma del módulo HV-CONTAINER · plataforma perimetral de 120 mm | {"boundingBoxM":{"min":[53.956207,77.885983,2.48],"max":[65.888264,84.434835,2.6]},"extentsM":[11.932057,6.548852,0.12],"meshSurfaceM2":76.171996,"meshVolumeM3":4.17,"closedSolid":true,"basis":"Magnitudes de las mallas representadas, no cantidades certificadas de obra, compra o fabricación. Las partes pueden compartir superficies; no se suman como un despiece de materiales."} | {"profileId":"concrete_reinforced","name":"Hormigón armado · gris natural","materialName":"Hormigón armado · clase pendiente de confirmar","physicalMaterialStatus":"Clase no confirmada en la hoja de equipo","physicalMaterialSource":"Geometría de cimentación del fabricante; no se extrapola HA-30 de la nota de pedestales.","appearanceStatus":"criterio_visual","appearanceBasis":"Interpretación visual del material documental; el acabado, tono y parámetros PBR no son una especificación contractual.","note":"La apariencia gráfica no modifica ni confirma la especificación física del material."} | {"elementId":"found_0904_f8c6d0e535ad5c","ifcGuid":"1zU1L8wXjP$e$Z9XhBDncl","ifcClass":"IfcSlab","buildingId":"process_plant","buildingName":"Zona de separación de aire","sourceDocumentId":"LHD2609-JG00100-20260904","sourceRepresentationKind":"foundation"} | {"profileId":"concrete_reinforced","name":"Hormigón armado · gris natural","status":"criterio_visual","basis":"Interpretación visual del material documental; el acabado, tono y parámetros PBR no son una especificación contractual.","physicalMaterialUnchanged":true} | HV-CONTAINER | 553E/5544, 1DB82, 1DE55 | Hormigón armado · clase pendiente de confirmar | 1.38 | 1.5 | 34.75 | 4.17 | Sección y contornos del fabricante; incidencias conservadas | Hormigón armado · gris natural | found_0904_f8c6d0e535ad5c | Clase no confirmada en la hoja de equipo | Geometría de cimentación del fabricante; no se extrapola HA-30 de la nota de pedestales. | 11.35 | 5.05 | concrete_reinforced | [0.666667,0.662745,0.619608] | 0.96 | La planta general y algunos croquis de apoyo muestran dimensiones transversales distintas. Se usan el contorno de cimentación y los centros de pilares de la implantación general; sección de viga VC1 400 × 400 mm y vuelo a 1050 mm del eje según detalle. / La capa de mortero sobre la losa no tiene una referencia vertical inequívoca; no se duplica una capa independiente en esa losa.
Cimentación y plataforma del módulo IC-CONTAINER · capa de limpieza | Hormigón de limpieza HA-20 | 6.50115 | 13.5292 | 0.1 | 285 | 285.1 | 127.705 | 6.2075 | {"documentId":"LHD2609-JG00100-20260904","title":"Cimentaciones de equipos y pedestales del fabricante · revisión recibida 04/09/2026","date":"2026-09-04","sheet":"15–15","fileName":"LHD2609-JG00100_20260904.dwg","revisionCaveat":"Fecha de revisión tomada del nombre recibido; cajetines internos mantienen 02/07/2026 y algunos textos de plantilla.","sourceFileSha256":"b42eb027b7bc0b14c38d1d13514f4899b58a732aa8d0ba2ccf10fa2fc3192890"} | {"name":"Hormigón de limpieza HA-20","status":"documentado","source":"Secciones del fabricante: capa de limpieza de 100 mm; nota 2CED5"} | {"documented":[{"label":"Extensión local X","value":4.775,"unit":"m","source":"5645/5652, 1DB82, 1DE55","status":"derivada del contorno CAD"},{"label":"Extensión local Y","value":13.0,"unit":"m","source":"5645/5652, 1DB82, 1DE55","status":"derivada del contorno CAD"},{"label":"Cota inferior relativa adoptada","value":-1.1,"unit":"m","source":"15–15","status":"interpretación con conflicto conservado"},{"label":"Cota superior relativa adoptada","value":-1,"unit":"m","source":"15–15","status":"documentada / separación por material"}],"geometry":[{"label":"Extensión de la malla en X","value":6.501151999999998,"unit":"m","source":"Geometría releída del IFC; datum absoluto de proceso provisional","status":"derivado"},{"label":"Extensión de la malla en Y","value":13.529225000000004,"unit":"m","source":"Geometría releída del IFC; datum absoluto de proceso provisional","status":"derivado"},{"label":"Extensión de la malla en Z","value":0.1,"unit":"m","source":"Geometría releída del IFC; datum absoluto de proceso provisional","status":"derivado"},{"label":"Cota inferior de visualización","value":285.0,"unit":"m","source":"Geometría releída del IFC; datum absoluto de proceso provisional","status":"derivado"},{"label":"Cota superior de visualización","value":285.1,"unit":"m","source":"Geometría releída del IFC; datum absoluto de proceso provisional","status":"derivado"}]} | ["La planta general y algunos croquis de apoyo muestran dimensiones transversales distintas. Se usan el contorno de cimentación y los centros de pilares de la implantación general; sección de viga VC1 400 × 400 mm y vuelo a 1050 mm del eje según detalle.","La capa de mortero sobre la losa no tiene una referencia vertical inequívoca; no se duplica una capa independiente en esa losa."] | {"Cota inferior relativa (m)":-1.1,"Cota superior relativa (m)":-1,"Cero absoluto de visualización (m)":286.1,"Estado del cero absoluto":"Provisional","Criterio":"Las cotas relativas proceden del dibujo; la equivalencia absoluta no está confirmada."} | F-IC-CONTAINER | ["IC-CONTAINER"] | [] | 15–15 | ["5645/5652","1DB82","1DE55"] | F-IC-CONTAINER/Cimentación y plataforma del módulo IC-CONTAINER · capa de limpieza | {"boundingBoxM":{"min":[36.525495,59.3748,0.0],"max":[43.026647,72.904025,0.1]},"extentsM":[6.501152,13.529225,0.1],"meshSurfaceM2":127.705006,"meshVolumeM3":6.2075,"closedSolid":true,"basis":"Magnitudes de las mallas representadas, no cantidades certificadas de obra, compra o fabricación. Las partes pueden compartir superficies; no se suman como un despiece de materiales."} | {"profileId":"concrete_ha20","name":"Hormigón de limpieza HA-20","materialName":"Hormigón de limpieza HA-20","physicalMaterialStatus":"documentado","physicalMaterialSource":"Secciones del fabricante: capa de limpieza de 100 mm; nota 2CED5","appearanceStatus":"criterio_visual","appearanceBasis":"Interpretación visual del material documental; el acabado, tono y parámetros PBR no son una especificación contractual.","note":"La apariencia gráfica no modifica ni confirma la especificación física del material."} | {"elementId":"found_0904_a8a3fbca2a122b","ifcGuid":"1_hy211UTLX9pugY_SCeCf","ifcClass":"IfcSlab","buildingId":"process_plant","buildingName":"Zona de separación de aire","sourceDocumentId":"LHD2609-JG00100-20260904","sourceRepresentationKind":"foundation"} | {"profileId":"concrete_ha20","name":"Hormigón de limpieza HA-20","status":"criterio_visual","basis":"Interpretación visual del material documental; el acabado, tono y parámetros PBR no son una especificación contractual.","physicalMaterialUnchanged":true} | IC-CONTAINER | 5645/5652, 1DB82, 1DE55 | Hormigón de limpieza HA-20 | -1.1 | -1 | 62.075 | 6.2075 | Sección y contornos del fabricante; incidencias conservadas | Hormigón de limpieza HA-20 | found_0904_a8a3fbca2a122b | documentado | Secciones del fabricante: capa de limpieza de 100 mm; nota 2CED5 | 4.775 | 13 | concrete_ha20 | [0.721569,0.709804,0.658824] | 0.98 | La planta general y algunos croquis de apoyo muestran dimensiones transversales distintas. Se usan el contorno de cimentación y los centros de pilares de la implantación general; sección de viga VC1 400 × 400 mm y vuelo a 1050 mm del eje según detalle. / La capa de mortero sobre la losa no tiene una referencia vertical inequívoca; no se duplica una capa independiente en esa losa.
Cimentación y plataforma del módulo IC-CONTAINER · plataforma perimetral de 120 mm |  | 6.6442 | 12.6255 | 0.12 | 287.48 | 287.6 | 80.008 | 4.38 | {"documentId":"LHD2609-JG00100-20260904","title":"Cimentaciones de equipos y pedestales del fabricante · revisión recibida 04/09/2026","date":"2026-09-04","sheet":"15–15","fileName":"LHD2609-JG00100_20260904.dwg","revisionCaveat":"Fecha de revisión tomada del nombre recibido; cajetines internos mantienen 02/07/2026 y algunos textos de plantilla.","sourceFileSha256":"b42eb027b7bc0b14c38d1d13514f4899b58a732aa8d0ba2ccf10fa2fc3192890"} | {"name":"Hormigón armado · clase pendiente de confirmar","status":"Clase no confirmada en la hoja de equipo","source":"Geometría de cimentación del fabricante; no se extrapola HA-30 de la nota de pedestales."} | {"documented":[{"label":"Extensión local X","value":5.05,"unit":"m","source":"5645/5652, 1DB82, 1DE55","status":"derivada del contorno CAD"},{"label":"Extensión local Y","value":12.05,"unit":"m","source":"5645/5652, 1DB82, 1DE55","status":"derivada del contorno CAD"},{"label":"Cota inferior relativa adoptada","value":1.38,"unit":"m","source":"15–15","status":"interpretación con conflicto conservado"},{"label":"Cota superior relativa adoptada","value":1.5,"unit":"m","source":"15–15","status":"documentada / separación por material"}],"geometry":[{"label":"Extensión de la malla en X","value":6.644195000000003,"unit":"m","source":"Geometría releída del IFC; datum absoluto de proceso provisional","status":"derivado"},{"label":"Extensión de la malla en Y","value":12.625534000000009,"unit":"m","source":"Geometría releída del IFC; datum absoluto de proceso provisional","status":"derivado"},{"label":"Extensión de la malla en Z","value":0.1200000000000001,"unit":"m","source":"Geometría releída del IFC; datum absoluto de proceso provisional","status":"derivado"},{"label":"Cota inferior de visualización","value":287.48,"unit":"m","source":"Geometría releída del IFC; datum absoluto de proceso provisional","status":"derivado"},{"label":"Cota superior de visualización","value":287.6,"unit":"m","source":"Geometría releída del IFC; datum absoluto de proceso provisional","status":"derivado"}]} | ["La planta general y algunos croquis de apoyo muestran dimensiones transversales distintas. Se usan el contorno de cimentación y los centros de pilares de la implantación general; sección de viga VC1 400 × 400 mm y vuelo a 1050 mm del eje según detalle.","La capa de mortero sobre la losa no tiene una referencia vertical inequívoca; no se duplica una capa independiente en esa losa."] | {"Cota inferior relativa (m)":1.38,"Cota superior relativa (m)":1.5,"Cero absoluto de visualización (m)":286.1,"Estado del cero absoluto":"Provisional","Criterio":"Las cotas relativas proceden del dibujo; la equivalencia absoluta no está confirmada."} | F-IC-CONTAINER | ["IC-CONTAINER"] | [] | 15–15 | ["5645/5652","1DB82","1DE55"] | F-IC-CONTAINER/Cimentación y plataforma del módulo IC-CONTAINER · plataforma perimetral de 120 mm | {"boundingBoxM":{"min":[36.88955,60.700461,2.48],"max":[43.533745,73.325995,2.6]},"extentsM":[6.644195,12.625534,0.12],"meshSurfaceM2":80.007999,"meshVolumeM3":4.38,"closedSolid":true,"basis":"Magnitudes de las mallas representadas, no cantidades certificadas de obra, compra o fabricación. Las partes pueden compartir superficies; no se suman como un despiece de materiales."} | {"profileId":"concrete_reinforced","name":"Hormigón armado · gris natural","materialName":"Hormigón armado · clase pendiente de confirmar","physicalMaterialStatus":"Clase no confirmada en la hoja de equipo","physicalMaterialSource":"Geometría de cimentación del fabricante; no se extrapola HA-30 de la nota de pedestales.","appearanceStatus":"criterio_visual","appearanceBasis":"Interpretación visual del material documental; el acabado, tono y parámetros PBR no son una especificación contractual.","note":"La apariencia gráfica no modifica ni confirma la especificación física del material."} | {"elementId":"found_0904_a62b23424415b1","ifcGuid":"1Z8pDbOLTLdBaLzq4al6Q2","ifcClass":"IfcSlab","buildingId":"process_plant","buildingName":"Zona de separación de aire","sourceDocumentId":"LHD2609-JG00100-20260904","sourceRepresentationKind":"foundation"} | {"profileId":"concrete_reinforced","name":"Hormigón armado · gris natural","status":"criterio_visual","basis":"Interpretación visual del material documental; el acabado, tono y parámetros PBR no son una especificación contractual.","physicalMaterialUnchanged":true} | IC-CONTAINER | 5645/5652, 1DB82, 1DE55 | Hormigón armado · clase pendiente de confirmar | 1.38 | 1.5 | 36.5 | 4.38 | Sección y contornos del fabricante; incidencias conservadas | Hormigón armado · gris natural | found_0904_a62b23424415b1 | Clase no confirmada en la hoja de equipo | Geometría de cimentación del fabricante; no se extrapola HA-30 de la nota de pedestales. | 5.05 | 12.05 | concrete_reinforced | [0.666667,0.662745,0.619608] | 0.96 | La planta general y algunos croquis de apoyo muestran dimensiones transversales distintas. Se usan el contorno de cimentación y los centros de pilares de la implantación general; sección de viga VC1 400 × 400 mm y vuelo a 1050 mm del eje según detalle. / La capa de mortero sobre la losa no tiene una referencia vertical inequívoca; no se duplica una capa independiente en esa losa.
Cimentación y plataforma del módulo MV-CONTAINER · capa de limpieza | Hormigón de limpieza HA-20 | 10.359 | 6.0653 | 0.1 | 285 | 285.1 | 96.505 | 4.6795 | {"documentId":"LHD2609-JG00100-20260904","title":"Cimentaciones de equipos y pedestales del fabricante · revisión recibida 04/09/2026","date":"2026-09-04","sheet":"16–16","fileName":"LHD2609-JG00100_20260904.dwg","revisionCaveat":"Fecha de revisión tomada del nombre recibido; cajetines internos mantienen 02/07/2026 y algunos textos de plantilla.","sourceFileSha256":"b42eb027b7bc0b14c38d1d13514f4899b58a732aa8d0ba2ccf10fa2fc3192890"} | {"name":"Hormigón de limpieza HA-20","status":"documentado","source":"Secciones del fabricante: capa de limpieza de 100 mm; nota 2CED5"} | {"documented":[{"label":"Extensión local X","value":9.8,"unit":"m","source":"5599/559F, 1DB82, 1DE55","status":"derivada del contorno CAD"},{"label":"Extensión local Y","value":4.775,"unit":"m","source":"5599/559F, 1DB82, 1DE55","status":"derivada del contorno CAD"},{"label":"Cota inferior relativa adoptada","value":-1.1,"unit":"m","source":"16–16","status":"interpretación con conflicto conservado"},{"label":"Cota superior relativa adoptada","value":-1,"unit":"m","source":"16–16","status":"documentada / separación por material"}],"geometry":[{"label":"Extensión de la malla en X","value":10.359045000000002,"unit":"m","source":"Geometría releída del IFC; datum absoluto de proceso provisional","status":"derivado"},{"label":"Extensión de la malla en Y","value":6.0652999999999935,"unit":"m","source":"Geometría releída del IFC; datum absoluto de proceso provisional","status":"derivado"},{"label":"Extensión de la malla en Z","value":0.1,"unit":"m","source":"Geometría releída del IFC; datum absoluto de proceso provisional","status":"derivado"},{"label":"Cota inferior de visualización","value":285.0,"unit":"m","source":"Geometría releída del IFC; datum absoluto de proceso provisional","status":"derivado"},{"label":"Cota superior de visualización","value":285.1,"unit":"m","source":"Geometría releída del IFC; datum absoluto de proceso provisional","status":"derivado"}]} | ["La planta general y algunos croquis de apoyo muestran dimensiones transversales distintas. Se usan el contorno de cimentación y los centros de pilares de la implantación general; sección de viga VC1 400 × 400 mm y vuelo a 1050 mm del eje según detalle.","La capa de mortero sobre la losa no tiene una referencia vertical inequívoca; no se duplica una capa independiente en esa losa."] | {"Cota inferior relativa (m)":-1.1,"Cota superior relativa (m)":-1,"Cero absoluto de visualización (m)":286.1,"Estado del cero absoluto":"Provisional","Criterio":"Las cotas relativas proceden del dibujo; la equivalencia absoluta no está confirmada."} | F-MV-CONTAINER | ["MV-CONTAINER"] | [] | 16–16 | ["5599/559F","1DB82","1DE55"] | F-MV-CONTAINER/Cimentación y plataforma del módulo MV-CONTAINER · capa de limpieza | {"boundingBoxM":{"min":[44.605536,79.83691,0.0],"max":[54.964581,85.90221,0.1]},"extentsM":[10.359045,6.0653,0.1],"meshSurfaceM2":96.505,"meshVolumeM3":4.6795,"closedSolid":true,"basis":"Magnitudes de las mallas representadas, no cantidades certificadas de obra, compra o fabricación. Las partes pueden compartir superficies; no se suman como un despiece de materiales."} | {"profileId":"concrete_ha20","name":"Hormigón de limpieza HA-20","materialName":"Hormigón de limpieza HA-20","physicalMaterialStatus":"documentado","physicalMaterialSource":"Secciones del fabricante: capa de limpieza de 100 mm; nota 2CED5","appearanceStatus":"criterio_visual","appearanceBasis":"Interpretación visual del material documental; el acabado, tono y parámetros PBR no son una especificación contractual.","note":"La apariencia gráfica no modifica ni confirma la especificación física del material."} | {"elementId":"found_0904_5437d20ca4a5e2","ifcGuid":"2nNBOqMlfRcgwnXhrHv_bE","ifcClass":"IfcSlab","buildingId":"process_plant","buildingName":"Zona de separación de aire","sourceDocumentId":"LHD2609-JG00100-20260904","sourceRepresentationKind":"foundation"} | {"profileId":"concrete_ha20","name":"Hormigón de limpieza HA-20","status":"criterio_visual","basis":"Interpretación visual del material documental; el acabado, tono y parámetros PBR no son una especificación contractual.","physicalMaterialUnchanged":true} | MV-CONTAINER | 5599/559F, 1DB82, 1DE55 | Hormigón de limpieza HA-20 | -1.1 | -1 | 46.795 | 4.6795 | Sección y contornos del fabricante; incidencias conservadas | Hormigón de limpieza HA-20 | found_0904_5437d20ca4a5e2 | documentado | Secciones del fabricante: capa de limpieza de 100 mm; nota 2CED5 | 9.8 | 4.775 | concrete_ha20 | [0.721569,0.709804,0.658824] | 0.98 | La planta general y algunos croquis de apoyo muestran dimensiones transversales distintas. Se usan el contorno de cimentación y los centros de pilares de la implantación general; sección de viga VC1 400 × 400 mm y vuelo a 1050 mm del eje según detalle. / La capa de mortero sobre la losa no tiene una referencia vertical inequívoca; no se duplica una capa independiente en esa losa.
Cimentación y plataforma del módulo MV-CONTAINER · plataforma perimetral de 120 mm |  | 9.45536 | 6.20834 | 0.12 | 287.48 | 287.6 | 62.472 | 3.42 | {"documentId":"LHD2609-JG00100-20260904","title":"Cimentaciones de equipos y pedestales del fabricante · revisión recibida 04/09/2026","date":"2026-09-04","sheet":"16–16","fileName":"LHD2609-JG00100_20260904.dwg","revisionCaveat":"Fecha de revisión tomada del nombre recibido; cajetines internos mantienen 02/07/2026 y algunos textos de plantilla.","sourceFileSha256":"b42eb027b7bc0b14c38d1d13514f4899b58a732aa8d0ba2ccf10fa2fc3192890"} | {"name":"Hormigón armado · clase pendiente de confirmar","status":"Clase no confirmada en la hoja de equipo","source":"Geometría de cimentación del fabricante; no se extrapola HA-30 de la nota de pedestales."} | {"documented":[{"label":"Extensión local X","value":8.85,"unit":"m","source":"5599/559F, 1DB82, 1DE55","status":"derivada del contorno CAD"},{"label":"Extensión local Y","value":5.05,"unit":"m","source":"5599/559F, 1DB82, 1DE55","status":"derivada del contorno CAD"},{"label":"Cota inferior relativa adoptada","value":1.38,"unit":"m","source":"16–16","status":"interpretación con conflicto conservado"},{"label":"Cota superior relativa adoptada","value":1.5,"unit":"m","source":"16–16","status":"documentada / separación por material"}],"geometry":[{"label":"Extensión de la malla en X","value":9.455355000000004,"unit":"m","source":"Geometría releída del IFC; datum absoluto de proceso provisional","status":"derivado"},{"label":"Extensión de la malla en Y","value":6.208342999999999,"unit":"m","source":"Geometría releída del IFC; datum absoluto de proceso provisional","status":"derivado"},{"label":"Extensión de la malla en Z","value":0.1200000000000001,"unit":"m","source":"Geometría releída del IFC; datum absoluto de proceso provisional","status":"derivado"},{"label":"Cota inferior de visualización","value":287.48,"unit":"m","source":"Geometría releída del IFC; datum absoluto de proceso provisional","status":"derivado"},{"label":"Cota superior de visualización","value":287.6,"unit":"m","source":"Geometría releída del IFC; datum absoluto de proceso provisional","status":"derivado"}]} | ["La planta general y algunos croquis de apoyo muestran dimensiones transversales distintas. Se usan el contorno de cimentación y los centros de pilares de la implantación general; sección de viga VC1 400 × 400 mm y vuelo a 1050 mm del eje según detalle.","La capa de mortero sobre la losa no tiene una referencia vertical inequívoca; no se duplica una capa independiente en esa losa."] | {"Cota inferior relativa (m)":1.38,"Cota superior relativa (m)":1.5,"Cero absoluto de visualización (m)":286.1,"Estado del cero absoluto":"Provisional","Criterio":"Las cotas relativas proceden del dibujo; la equivalencia absoluta no está confirmada."} | F-MV-CONTAINER | ["MV-CONTAINER"] | [] | 16–16 | ["5599/559F","1DB82","1DE55"] | F-MV-CONTAINER/Cimentación y plataforma del módulo MV-CONTAINER · plataforma perimetral de 120 mm | {"boundingBoxM":{"min":[45.931197,79.329812,2.48],"max":[55.386552,85.538155,2.6]},"extentsM":[9.455355,6.208343,0.12],"meshSurfaceM2":62.471998,"meshVolumeM3":3.42,"closedSolid":true,"basis":"Magnitudes de las mallas representadas, no cantidades certificadas de obra, compra o fabricación. Las partes pueden compartir superficies; no se suman como un despiece de materiales."} | {"profileId":"concrete_reinforced","name":"Hormigón armado · gris natural","materialName":"Hormigón armado · clase pendiente de confirmar","physicalMaterialStatus":"Clase no confirmada en la hoja de equipo","physicalMaterialSource":"Geometría de cimentación del fabricante; no se extrapola HA-30 de la nota de pedestales.","appearanceStatus":"criterio_visual","appearanceBasis":"Interpretación visual del material documental; el acabado, tono y parámetros PBR no son una especificación contractual.","note":"La apariencia gráfica no modifica ni confirma la especificación física del material."} | {"elementId":"found_0904_40371ce5cfe23e","ifcGuid":"2hMxNVXIzQJgzxqoDV0FWH","ifcClass":"IfcSlab","buildingId":"process_plant","buildingName":"Zona de separación de aire","sourceDocumentId":"LHD2609-JG00100-20260904","sourceRepresentationKind":"foundation"} | {"profileId":"concrete_reinforced","name":"Hormigón armado · gris natural","status":"criterio_visual","basis":"Interpretación visual del material documental; el acabado, tono y parámetros PBR no son una especificación contractual.","physicalMaterialUnchanged":true} | MV-CONTAINER | 5599/559F, 1DB82, 1DE55 | Hormigón armado · clase pendiente de confirmar | 1.38 | 1.5 | 28.5 | 3.42 | Sección y contornos del fabricante; incidencias conservadas | Hormigón armado · gris natural | found_0904_40371ce5cfe23e | Clase no confirmada en la hoja de equipo | Geometría de cimentación del fabricante; no se extrapola HA-30 de la nota de pedestales. | 8.85 | 5.05 | concrete_reinforced | [0.666667,0.662745,0.619608] | 0.96 | La planta general y algunos croquis de apoyo muestran dimensiones transversales distintas. Se usan el contorno de cimentación y los centros de pilares de la implantación general; sección de viga VC1 400 × 400 mm y vuelo a 1050 mm del eje según detalle. / La capa de mortero sobre la losa no tiene una referencia vertical inequívoca; no se duplica una capa independiente en esa losa.
Cimentación de soporte de tuberías C01 · capa de limpieza | Hormigón de limpieza HA-20 | 1.35226 | 1.35226 | 0.1 | 285 | 285.1 | 3.36 | 0.144 | {"documentId":"LHD2609-JG00100-20260904","title":"Cimentaciones de equipos y pedestales del fabricante · revisión recibida 04/09/2026","date":"2026-09-04","sheet":"ZD1 / DZ-1","fileName":"LHD2609-JG00100_20260904.dwg","revisionCaveat":"Fecha de revisión tomada del nombre recibido; cajetines internos mantienen 02/07/2026 y algunos textos de plantilla.","sourceFileSha256":"b42eb027b7bc0b14c38d1d13514f4899b58a732aa8d0ba2ccf10fa2fc3192890"} | {"name":"Hormigón de limpieza HA-20","status":"documentado","source":"Secciones del fabricante: capa de limpieza de 100 mm; nota 2CED5"} | {"documented":[{"label":"Extensión local X","value":1.2,"unit":"m","source":"2CC56, 2CC2F, 2CCC9, 2CC64, 2CC21, 2CC28, 2CCA9, 2CEA7, 2CE82","status":"derivada del contorno CAD"},{"label":"Extensión local Y","value":1.2,"unit":"m","source":"2CC56, 2CC2F, 2CCC9, 2CC64, 2CC21, 2CC28, 2CCA9, 2CEA7, 2CE82","status":"derivada del contorno CAD"},{"label":"Cota inferior relativa adoptada","value":-1.1,"unit":"m","source":"ZD1 / DZ-1","status":"documentada"},{"label":"Cota superior relativa adoptada","value":-1.0,"unit":"m","source":"ZD1 / DZ-1","status":"documentada / separación por material"}],"geometry":[{"label":"Extensión de la malla en X","value":1.3522620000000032,"unit":"m","source":"Geometría releída del IFC; datum absoluto de proceso provisional","status":"derivado"},{"label":"Extensión de la malla en Y","value":1.3522620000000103,"unit":"m","source":"Geometría releída del IFC; datum absoluto de proceso provisional","status":"derivado"},{"label":"Extensión de la malla en Z","value":0.1,"unit":"m","source":"Geometría releída del IFC; datum absoluto de proceso provisional","status":"derivado"},{"label":"Cota inferior de visualización","value":285.0,"unit":"m","source":"Geometría releída del IFC; datum absoluto de proceso provisional","status":"derivado"},{"label":"Cota superior de visualización","value":285.1,"unit":"m","source":"Geometría releída del IFC; datum absoluto de proceso provisional","status":"derivado"}]} | [] | {"Cota inferior relativa (m)":-1.1,"Cota superior relativa (m)":-1.0,"Cero absoluto de visualización (m)":286.1,"Estado del cero absoluto":"Provisional","Criterio":"Las cotas relativas proceden del dibujo; la equivalencia absoluta no está confirmada."} | SUP-C01 | [] | ["C01"] | ZD1 / DZ-1 | ["2CC56","2CC2F","2CCC9","2CC64","2CC21","2CC28","2CCA9","2CEA7","2CE82"] | SUP-C01/Cimentación de soporte de tuberías C01 · capa de limpieza | {"boundingBoxM":{"min":[47.694196,78.690981,0.0],"max":[49.046458,80.043243,0.1]},"extentsM":[1.352262,1.352262,0.1],"meshSurfaceM2":3.36,"meshVolumeM3":0.144,"closedSolid":true,"basis":"Magnitudes de las mallas representadas, no cantidades certificadas de obra, compra o fabricación. Las partes pueden compartir superficies; no se suman como un despiece de materiales."} | {"profileId":"concrete_ha20","name":"Hormigón de limpieza HA-20","materialName":"Hormigón de limpieza HA-20","physicalMaterialStatus":"documentado","physicalMaterialSource":"Secciones del fabricante: capa de limpieza de 100 mm; nota 2CED5","appearanceStatus":"criterio_visual","appearanceBasis":"Interpretación visual del material documental; el acabado, tono y parámetros PBR no son una especificación contractual.","note":"La apariencia gráfica no modifica ni confirma la especificación física del material."} | {"elementId":"found_0904_ada385d76826ce","ifcGuid":"0O2GSqJrPKFvE$TZvMgZV7","ifcClass":"IfcSlab","buildingId":"process_plant","buildingName":"Zona de separación de aire","sourceDocumentId":"LHD2609-JG00100-20260904","sourceRepresentationKind":"foundation"} | {"profileId":"concrete_ha20","name":"Hormigón de limpieza HA-20","status":"criterio_visual","basis":"Interpretación visual del material documental; el acabado, tono y parámetros PBR no son una especificación contractual.","physicalMaterialUnchanged":true} |  | 2CC56, 2CC2F, 2CCC9, 2CC64, 2CC21, 2CC28, 2CCA9, 2CEA7, 2CE82 | Hormigón de limpieza HA-20 | -1.1 | -1 | 1.44 | 0.144 | Contornos y sección documentados por el fabricante | Hormigón de limpieza HA-20 | found_0904_ada385d76826ce | documentado | Secciones del fabricante: capa de limpieza de 100 mm; nota 2CED5 | 1.2 | 1.2 | concrete_ha20 | [0.721569,0.709804,0.658824] | 0.98
Cimentación de soporte de tuberías C02 · capa de limpieza | Hormigón de limpieza HA-20 | 1.35226 | 1.35226 | 0.1 | 285 | 285.1 | 3.36 | 0.144 | {"documentId":"LHD2609-JG00100-20260904","title":"Cimentaciones de equipos y pedestales del fabricante · revisión recibida 04/09/2026","date":"2026-09-04","sheet":"ZD1 / DZ-1","fileName":"LHD2609-JG00100_20260904.dwg","revisionCaveat":"Fecha de revisión tomada del nombre recibido; cajetines internos mantienen 02/07/2026 y algunos textos de plantilla.","sourceFileSha256":"b42eb027b7bc0b14c38d1d13514f4899b58a732aa8d0ba2ccf10fa2fc3192890"} | {"name":"Hormigón de limpieza HA-20","status":"documentado","source":"Secciones del fabricante: capa de limpieza de 100 mm; nota 2CED5"} | {"documented":[{"label":"Extensión local X","value":1.2,"unit":"m","source":"2CC57, 2CD32, 2CD35, 2CD33, 2CD30, 2CD31, 2CD34, 2CEA8, 2CE83","status":"derivada del contorno CAD"},{"label":"Extensión local Y","value":1.2,"unit":"m","source":"2CC57, 2CD32, 2CD35, 2CD33, 2CD30, 2CD31, 2CD34, 2CEA8, 2CE83","status":"derivada del contorno CAD"},{"label":"Cota inferior relativa adoptada","value":-1.1,"unit":"m","source":"ZD1 / DZ-1","status":"documentada"},{"label":"Cota superior relativa adoptada","value":-1.0,"unit":"m","source":"ZD1 / DZ-1","status":"documentada / separación por material"}],"geometry":[{"label":"Extensión de la malla en X","value":1.3522620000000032,"unit":"m","source":"Geometría releída del IFC; datum absoluto de proceso provisional","status":"derivado"},{"label":"Extensión de la malla en Y","value":1.352261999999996,"unit":"m","source":"Geometría releída del IFC; datum absoluto de proceso provisional","status":"derivado"},{"label":"Extensión de la malla en Z","value":0.1,"unit":"m","source":"Geometría releída del IFC; datum absoluto de proceso provisional","status":"derivado"},{"label":"Cota inferior de visualización","value":285.0,"unit":"m","source":"Geometría releída del IFC; datum absoluto de proceso provisional","status":"derivado"},{"label":"Cota superior de visualización","value":285.1,"unit":"m","source":"Geometría releída del IFC; datum absoluto de proceso provisional","status":"derivado"}]} | [] | {"Cota inferior relativa (m)":-1.1,"Cota superior relativa (m)":-1.0,"Cero absoluto de visualización (m)":286.1,"Estado del cero absoluto":"Provisional","Criterio":"Las cotas relativas proceden del dibujo; la equivalencia absoluta no está confirmada."} | SUP-C02 | [] | ["C02"] | ZD1 / DZ-1 | ["2CC57","2CD32","2CD35","2CD33","2CD30","2CD31","2CD34","2CEA8","2CE83"] | SUP-C02/Cimentación de soporte de tuberías C02 · capa de limpieza | {"boundingBoxM":{"min":[47.554587,77.675533,0.0],"max":[48.906849,79.027795,0.1]},"extentsM":[1.352262,1.352262,0.1],"meshSurfaceM2":3.36,"meshVolumeM3":0.144,"closedSolid":true,"basis":"Magnitudes de las mallas representadas, no cantidades certificadas de obra, compra o fabricación. Las partes pueden compartir superficies; no se suman como un despiece de materiales."} | {"profileId":"concrete_ha20","name":"Hormigón de limpieza HA-20","materialName":"Hormigón de limpieza HA-20","physicalMaterialStatus":"documentado","physicalMaterialSource":"Secciones del fabricante: capa de limpieza de 100 mm; nota 2CED5","appearanceStatus":"criterio_visual","appearanceBasis":"Interpretación visual del material documental; el acabado, tono y parámetros PBR no son una especificación contractual.","note":"La apariencia gráfica no modifica ni confirma la especificación física del material."} | {"elementId":"found_0904_23e95771645377","ifcGuid":"0R8nYTE25VkgOB$XQSOjcM","ifcClass":"IfcSlab","buildingId":"process_plant","buildingName":"Zona de separación de aire","sourceDocumentId":"LHD2609-JG00100-20260904","sourceRepresentationKind":"foundation"} | {"profileId":"concrete_ha20","name":"Hormigón de limpieza HA-20","status":"criterio_visual","basis":"Interpretación visual del material documental; el acabado, tono y parámetros PBR no son una especificación contractual.","physicalMaterialUnchanged":true} |  | 2CC57, 2CD32, 2CD35, 2CD33, 2CD30, 2CD31, 2CD34, 2CEA8, 2CE83 | Hormigón de limpieza HA-20 | -1.1 | -1 | 1.44 | 0.144 | Contornos y sección documentados por el fabricante | Hormigón de limpieza HA-20 | found_0904_23e95771645377 | documentado | Secciones del fabricante: capa de limpieza de 100 mm; nota 2CED5 | 1.2 | 1.2 | concrete_ha20 | [0.721569,0.709804,0.658824] | 0.98
Cimentación de soporte de tuberías C03 · capa de limpieza | Hormigón de limpieza HA-20 | 1.35226 | 1.35226 | 0.1 | 285 | 285.1 | 3.36 | 0.144 | {"documentId":"LHD2609-JG00100-20260904","title":"Cimentaciones de equipos y pedestales del fabricante · revisión recibida 04/09/2026","date":"2026-09-04","sheet":"ZD1 / DZ-1","fileName":"LHD2609-JG00100_20260904.dwg","revisionCaveat":"Fecha de revisión tomada del nombre recibido; cajetines internos mantienen 02/07/2026 y algunos textos de plantilla.","sourceFileSha256":"b42eb027b7bc0b14c38d1d13514f4899b58a732aa8d0ba2ccf10fa2fc3192890"} | {"name":"Hormigón de limpieza HA-20","status":"documentado","source":"Secciones del fabricante: capa de limpieza de 100 mm; nota 2CED5"} | {"documented":[{"label":"Extensión local X","value":1.2,"unit":"m","source":"2CC58, 2CD38, 2CD3B, 2CD39, 2CD36, 2CD37, 2CD3A, 2CEA9, 2CE84","status":"derivada del contorno CAD"},{"label":"Extensión local Y","value":1.2,"unit":"m","source":"2CC58, 2CD38, 2CD3B, 2CD39, 2CD36, 2CD37, 2CD3A, 2CEA9, 2CE84","status":"derivada del contorno CAD"},{"label":"Cota inferior relativa adoptada","value":-1.1,"unit":"m","source":"ZD1 / DZ-1","status":"documentada"},{"label":"Cota superior relativa adoptada","value":-1.0,"unit":"m","source":"ZD1 / DZ-1","status":"documentada / separación por material"}],"geometry":[{"label":"Extensión de la malla en X","value":1.352261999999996,"unit":"m","source":"Geometría releída del IFC; datum absoluto de proceso provisional","status":"derivado"},{"label":"Extensión de la malla en Y","value":1.3522620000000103,"unit":"m","source":"Geometría releída del IFC; datum absoluto de proceso provisional","status":"derivado"},{"label":"Extensión de la malla en Z","value":0.1,"unit":"m","source":"Geometría releída del IFC; datum absoluto de proceso provisional","status":"derivado"},{"label":"Cota inferior de visualización","value":285.0,"unit":"m","source":"Geometría releída del IFC; datum absoluto de proceso provisional","status":"derivado"},{"label":"Cota superior de visualización","value":285.1,"unit":"m","source":"Geometría releída del IFC; datum absoluto de proceso provisional","status":"derivado"}]} | [] | {"Cota inferior relativa (m)":-1.1,"Cota superior relativa (m)":-1.0,"Cero absoluto de visualización (m)":286.1,"Estado del cero absoluto":"Provisional","Criterio":"Las cotas relativas proceden del dibujo; la equivalencia absoluta no está confirmada."} | SUP-C03 | [] | ["C03"] | ZD1 / DZ-1 | ["2CC58","2CD38","2CD3B","2CD39","2CD36","2CD37","2CD3A","2CEA9","2CE84"] | SUP-C03/Cimentación de soporte de tuberías C03 · capa de limpieza | {"boundingBoxM":{"min":[53.786883,77.853327,0.0],"max":[55.139145,79.205589,0.1]},"extentsM":[1.352262,1.352262,0.1],"meshSurfaceM2":3.36,"meshVolumeM3":0.144,"closedSolid":true,"basis":"Magnitudes de las mallas representadas, no cantidades certificadas de obra, compra o fabricación. Las partes pueden compartir superficies; no se suman como un despiece de materiales."} | {"profileId":"concrete_ha20","name":"Hormigón de limpieza HA-20","materialName":"Hormigón de limpieza HA-20","physicalMaterialStatus":"documentado","physicalMaterialSource":"Secciones del fabricante: capa de limpieza de 100 mm; nota 2CED5","appearanceStatus":"criterio_visual","appearanceBasis":"Interpretación visual del material documental; el acabado, tono y parámetros PBR no son una especificación contractual.","note":"La apariencia gráfica no modifica ni confirma la especificación física del material."} | {"elementId":"found_0904_6568ca20b5b904","ifcGuid":"1Iu0CykgfPxQxbhVY8VVrB","ifcClass":"IfcSlab","buildingId":"process_plant","buildingName":"Zona de separación de aire","sourceDocumentId":"LHD2609-JG00100-20260904","sourceRepresentationKind":"foundation"} | {"profileId":"concrete_ha20","name":"Hormigón de limpieza HA-20","status":"criterio_visual","basis":"Interpretación visual del material documental; el acabado, tono y parámetros PBR no son una especificación contractual.","physicalMaterialUnchanged":true} |  | 2CC58, 2CD38, 2CD3B, 2CD39, 2CD36, 2CD37, 2CD3A, 2CEA9, 2CE84 | Hormigón de limpieza HA-20 | -1.1 | -1 | 1.44 | 0.144 | Contornos y sección documentados por el fabricante | Hormigón de limpieza HA-20 | found_0904_6568ca20b5b904 | documentado | Secciones del fabricante: capa de limpieza de 100 mm; nota 2CED5 | 1.2 | 1.2 | concrete_ha20 | [0.721569,0.709804,0.658824] | 0.98
Cimentación de soporte de tuberías C04 · capa de limpieza | Hormigón de limpieza HA-20 | 1.35226 | 1.35226 | 0.1 | 285 | 285.1 | 3.36 | 0.144 | {"documentId":"LHD2609-JG00100-20260904","title":"Cimentaciones de equipos y pedestales del fabricante · revisión recibida 04/09/2026","date":"2026-09-04","sheet":"ZD1 / DZ-1","fileName":"LHD2609-JG00100_20260904.dwg","revisionCaveat":"Fecha de revisión tomada del nombre recibido; cajetines internos mantienen 02/07/2026 y algunos textos de plantilla.","sourceFileSha256":"b42eb027b7bc0b14c38d1d13514f4899b58a732aa8d0ba2ccf10fa2fc3192890"} | {"name":"Hormigón de limpieza HA-20","status":"documentado","source":"Secciones del fabricante: capa de limpieza de 100 mm; nota 2CED5"} | {"documented":[{"label":"Extensión local X","value":1.2,"unit":"m","source":"2CC59, 2CD3E, 2CD41, 2CD3F, 2CD3C, 2CD3D, 2CD40, 2CEAA, 2CE85","status":"derivada del contorno CAD"},{"label":"Extensión local Y","value":1.2,"unit":"m","source":"2CC59, 2CD3E, 2CD41, 2CD3F, 2CD3C, 2CD3D, 2CD40, 2CEAA, 2CE85","status":"derivada del contorno CAD"},{"label":"Cota inferior relativa adoptada","value":-1.1,"unit":"m","source":"ZD1 / DZ-1","status":"documentada"},{"label":"Cota superior relativa adoptada","value":-1.0,"unit":"m","source":"ZD1 / DZ-1","status":"documentada / separación por material"}],"geometry":[{"label":"Extensión de la malla en X","value":1.352261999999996,"unit":"m","source":"Geometría releída del IFC; datum absoluto de proceso provisional","status":"derivado"},{"label":"Extensión de la malla en Y","value":1.352261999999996,"unit":"m","source":"Geometría releída del IFC; datum absoluto de proceso provisional","status":"derivado"},{"label":"Extensión de la malla en Z","value":0.1,"unit":"m","source":"Geometría releída del IFC; datum absoluto de proceso provisional","status":"derivado"},{"label":"Cota inferior de visualización","value":285.0,"unit":"m","source":"Geometría releída del IFC; datum absoluto de proceso provisional","status":"derivado"},{"label":"Cota superior de visualización","value":285.1,"unit":"m","source":"Geometría releída del IFC; datum absoluto de proceso provisional","status":"derivado"}]} | [] | {"Cota inferior relativa (m)":-1.1,"Cota superior relativa (m)":-1.0,"Cero absoluto de visualización (m)":286.1,"Estado del cero absoluto":"Provisional","Criterio":"Las cotas relativas proceden del dibujo; la equivalencia absoluta no está confirmada."} | SUP-C04 | [] | ["C04"] | ZD1 / DZ-1 | ["2CC59","2CD3E","2CD41","2CD3F","2CD3C","2CD3D","2CD40","2CEAA","2CE85"] | SUP-C04/Cimentación de soporte de tuberías C04 · capa de limpieza | {"boundingBoxM":{"min":[53.647274,76.837879,0.0],"max":[54.999536,78.190141,0.1]},"extentsM":[1.352262,1.352262,0.1],"meshSurfaceM2":3.36,"meshVolumeM3":0.144,"closedSolid":true,"basis":"Magnitudes de las mallas representadas, no cantidades certificadas de obra, compra o fabricación. Las partes pueden compartir superficies; no se suman como un despiece de materiales."} | {"profileId":"concrete_ha20","name":"Hormigón de limpieza HA-20","materialName":"Hormigón de limpieza HA-20","physicalMaterialStatus":"documentado","physicalMaterialSource":"Secciones del fabricante: capa de limpieza de 100 mm; nota 2CED5","appearanceStatus":"criterio_visual","appearanceBasis":"Interpretación visual del material documental; el acabado, tono y parámetros PBR no son una especificación contractual.","note":"La apariencia gráfica no modifica ni confirma la especificación física del material."} | {"elementId":"found_0904_4fe72355fa6239","ifcGuid":"2S58gAtYzVpQObPADRWXPY","ifcClass":"IfcSlab","buildingId":"process_plant","buildingName":"Zona de separación de aire","sourceDocumentId":"LHD2609-JG00100-20260904","sourceRepresentationKind":"foundation"} | {"profileId":"concrete_ha20","name":"Hormigón de limpieza HA-20","status":"criterio_visual","basis":"Interpretación visual del material documental; el acabado, tono y parámetros PBR no son una especificación contractual.","physicalMaterialUnchanged":true} |  | 2CC59, 2CD3E, 2CD41, 2CD3F, 2CD3C, 2CD3D, 2CD40, 2CEAA, 2CE85 | Hormigón de limpieza HA-20 | -1.1 | -1 | 1.44 | 0.144 | Contornos y sección documentados por el fabricante | Hormigón de limpieza HA-20 | found_0904_4fe72355fa6239 | documentado | Secciones del fabricante: capa de limpieza de 100 mm; nota 2CED5 | 1.2 | 1.2 | concrete_ha20 | [0.721569,0.709804,0.658824] | 0.98
Cimentación de soporte de tuberías C05 · capa de limpieza | Hormigón de limpieza HA-20 | 1.35226 | 1.35226 | 0.1 | 285 | 285.1 | 3.36 | 0.144 | {"documentId":"LHD2609-JG00100-20260904","title":"Cimentaciones de equipos y pedestales del fabricante · revisión recibida 04/09/2026","date":"2026-09-04","sheet":"ZD1 / DZ-1","fileName":"LHD2609-JG00100_20260904.dwg","revisionCaveat":"Fecha de revisión tomada del nombre recibido; cajetines internos mantienen 02/07/2026 y algunos textos de plantilla.","sourceFileSha256":"b42eb027b7bc0b14c38d1d13514f4899b58a732aa8d0ba2ccf10fa2fc3192890"} | {"name":"Hormigón de limpieza HA-20","status":"documentado","source":"Secciones del fabricante: capa de limpieza de 100 mm; nota 2CED5"} | {"documented":[{"label":"Extensión local X","value":1.2,"unit":"m","source":"2CC5A, 2CD42, 2CC62, 2CC66, 2CC22, 2CC29, 2CD67, 2CEAB, 2CE86","status":"derivada del contorno CAD"},{"label":"Extensión local Y","value":1.2,"unit":"m","source":"2CC5A, 2CD42, 2CC62, 2CC66, 2CC22, 2CC29, 2CD67, 2CEAB, 2CE86","status":"derivada del contorno CAD"},{"label":"Cota inferior relativa adoptada","value":-1.1,"unit":"m","source":"ZD1 / DZ-1","status":"documentada"},{"label":"Cota superior relativa adoptada","value":-1.0,"unit":"m","source":"ZD1 / DZ-1","status":"documentada / separación por material"}],"geometry":[{"label":"Extensión de la malla en X","value":1.3522620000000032,"unit":"m","source":"Geometría releída del IFC; datum absoluto de proceso provisional","status":"derivado"},{"label":"Extensión de la malla en Y","value":1.3522609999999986,"unit":"m","source":"Geometría releída del IFC; datum absoluto de proceso provisional","status":"derivado"},{"label":"Extensión de la malla en Z","value":0.1,"unit":"m","source":"Geometría releída del IFC; datum absoluto de proceso provisional","status":"derivado"},{"label":"Cota inferior de visualización","value":285.0,"unit":"m","source":"Geometría releída del IFC; datum absoluto de proceso provisional","status":"derivado"},{"label":"Cota superior de visualización","value":285.1,"unit":"m","source":"Geometría releída del IFC; datum absoluto de proceso provisional","status":"derivado"}]} | [] | {"Cota inferior relativa (m)":-1.1,"Cota superior relativa (m)":-1.0,"Cero absoluto de visualización (m)":286.1,"Estado del cero absoluto":"Provisional","Criterio":"Las cotas relativas proceden del dibujo; la equivalencia absoluta no está confirmada."} | SUP-C05 | [] | ["C05"] | ZD1 / DZ-1 | ["2CC5A","2CD42","2CC62","2CC66","2CC22","2CC29","2CD67","2CEAB","2CE86"] | SUP-C05/Cimentación de soporte de tuberías C05 · capa de limpieza | {"boundingBoxM":{"min":[59.978638,77.002053,0.0],"max":[61.3309,78.354314,0.1]},"extentsM":[1.352262,1.352261,0.1],"meshSurfaceM2":3.36,"meshVolumeM3":0.144,"closedSolid":true,"basis":"Magnitudes de las mallas representadas, no cantidades certificadas de obra, compra o fabricación. Las partes pueden compartir superficies; no se suman como un despiece de materiales."} | {"profileId":"concrete_ha20","name":"Hormigón de limpieza HA-20","materialName":"Hormigón de limpieza HA-20","physicalMaterialStatus":"documentado","physicalMaterialSource":"Secciones del fabricante: capa de limpieza de 100 mm; nota 2CED5","appearanceStatus":"criterio_visual","appearanceBasis":"Interpretación visual del material documental; el acabado, tono y parámetros PBR no son una especificación contractual.","note":"La apariencia gráfica no modifica ni confirma la especificación física del material."} | {"elementId":"found_0904_5c48bd77428fdd","ifcGuid":"2Y1QlzOSjSjfo3hXW35M9i","ifcClass":"IfcSlab","buildingId":"process_plant","buildingName":"Zona de separación de aire","sourceDocumentId":"LHD2609-JG00100-20260904","sourceRepresentationKind":"foundation"} | {"profileId":"concrete_ha20","name":"Hormigón de limpieza HA-20","status":"criterio_visual","basis":"Interpretación visual del material documental; el acabado, tono y parámetros PBR no son una especificación contractual.","physicalMaterialUnchanged":true} |  | 2CC5A, 2CD42, 2CC62, 2CC66, 2CC22, 2CC29, 2CD67, 2CEAB, 2CE86 | Hormigón de limpieza HA-20 | -1.1 | -1 | 1.44 | 0.144 | Contornos y sección documentados por el fabricante | Hormigón de limpieza HA-20 | found_0904_5c48bd77428fdd | documentado | Secciones del fabricante: capa de limpieza de 100 mm; nota 2CED5 | 1.2 | 1.2 | concrete_ha20 | [0.721569,0.709804,0.658824] | 0.98
Cimentación de soporte de tuberías C06 · capa de limpieza | Hormigón de limpieza HA-20 | 1.35226 | 1.35226 | 0.1 | 285 | 285.1 | 3.36 | 0.144 | {"documentId":"LHD2609-JG00100-20260904","title":"Cimentaciones de equipos y pedestales del fabricante · revisión recibida 04/09/2026","date":"2026-09-04","sheet":"ZD1 / DZ-1","fileName":"LHD2609-JG00100_20260904.dwg","revisionCaveat":"Fecha de revisión tomada del nombre recibido; cajetines internos mantienen 02/07/2026 y algunos textos de plantilla.","sourceFileSha256":"b42eb027b7bc0b14c38d1d13514f4899b58a732aa8d0ba2ccf10fa2fc3192890"} | {"name":"Hormigón de limpieza HA-20","status":"documentado","source":"Secciones del fabricante: capa de limpieza de 100 mm; nota 2CED5"} | {"documented":[{"label":"Extensión local X","value":1.2,"unit":"m","source":"2CC5B, 2CD43, 2CC63, 2CC67, 2CC23, 2CC2A, 2CD68, 2CEAC, 2CE87","status":"derivada del contorno CAD"},{"label":"Extensión local Y","value":1.2,"unit":"m","source":"2CC5B, 2CD43, 2CC63, 2CC67, 2CC23, 2CC2A, 2CD68, 2CEAC, 2CE87","status":"derivada del contorno CAD"},{"label":"Cota inferior relativa adoptada","value":-1.1,"unit":"m","source":"ZD1 / DZ-1","status":"documentada"},{"label":"Cota superior relativa adoptada","value":-1.0,"unit":"m","source":"ZD1 / DZ-1","status":"documentada / separación por material"}],"geometry":[{"label":"Extensión de la malla en X","value":1.3522620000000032,"unit":"m","source":"Geometría releída del IFC; datum absoluto de proceso provisional","status":"derivado"},{"label":"Extensión de la malla en Y","value":1.352261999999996,"unit":"m","source":"Geometría releída del IFC; datum absoluto de proceso provisional","status":"derivado"},{"label":"Extensión de la malla en Z","value":0.1,"unit":"m","source":"Geometría releída del IFC; datum absoluto de proceso provisional","status":"derivado"},{"label":"Cota inferior de visualización","value":285.0,"unit":"m","source":"Geometría releída del IFC; datum absoluto de proceso provisional","status":"derivado"},{"label":"Cota superior de visualización","value":285.1,"unit":"m","source":"Geometría releída del IFC; datum absoluto de proceso provisional","status":"derivado"}]} | [] | {"Cota inferior relativa (m)":-1.1,"Cota superior relativa (m)":-1.0,"Cero absoluto de visualización (m)":286.1,"Estado del cero absoluto":"Provisional","Criterio":"Las cotas relativas proceden del dibujo; la equivalencia absoluta no está confirmada."} | SUP-C06 | [] | ["C06"] | ZD1 / DZ-1 | ["2CC5B","2CD43","2CC63","2CC67","2CC23","2CC2A","2CD68","2CEAC","2CE87"] | SUP-C06/Cimentación de soporte de tuberías C06 · capa de limpieza | {"boundingBoxM":{"min":[59.839029,75.986605,0.0],"max":[61.191291,77.338867,0.1]},"extentsM":[1.352262,1.352262,0.1],"meshSurfaceM2":3.36,"meshVolumeM3":0.144,"closedSolid":true,"basis":"Magnitudes de las mallas representadas, no cantidades certificadas de obra, compra o fabricación. Las partes pueden compartir superficies; no se suman como un despiece de materiales."} | {"profileId":"concrete_ha20","name":"Hormigón de limpieza HA-20","materialName":"Hormigón de limpieza HA-20","physicalMaterialStatus":"documentado","physicalMaterialSource":"Secciones del fabricante: capa de limpieza de 100 mm; nota 2CED5","appearanceStatus":"criterio_visual","appearanceBasis":"Interpretación visual del material documental; el acabado, tono y parámetros PBR no son una especificación contractual.","note":"La apariencia gráfica no modifica ni confirma la especificación física del material."} | {"elementId":"found_0904_31fe536d528eb3","ifcGuid":"0sur2ulGrHXAj$fgib_s65","ifcClass":"IfcSlab","buildingId":"process_plant","buildingName":"Zona de separación de aire","sourceDocumentId":"LHD2609-JG00100-20260904","sourceRepresentationKind":"foundation"} | {"profileId":"concrete_ha20","name":"Hormigón de limpieza HA-20","status":"criterio_visual","basis":"Interpretación visual del material documental; el acabado, tono y parámetros PBR no son una especificación contractual.","physicalMaterialUnchanged":true} |  | 2CC5B, 2CD43, 2CC63, 2CC67, 2CC23, 2CC2A, 2CD68, 2CEAC, 2CE87 | Hormigón de limpieza HA-20 | -1.1 | -1 | 1.44 | 0.144 | Contornos y sección documentados por el fabricante | Hormigón de limpieza HA-20 | found_0904_31fe536d528eb3 | documentado | Secciones del fabricante: capa de limpieza de 100 mm; nota 2CED5 | 1.2 | 1.2 | concrete_ha20 | [0.721569,0.709804,0.658824] | 0.98
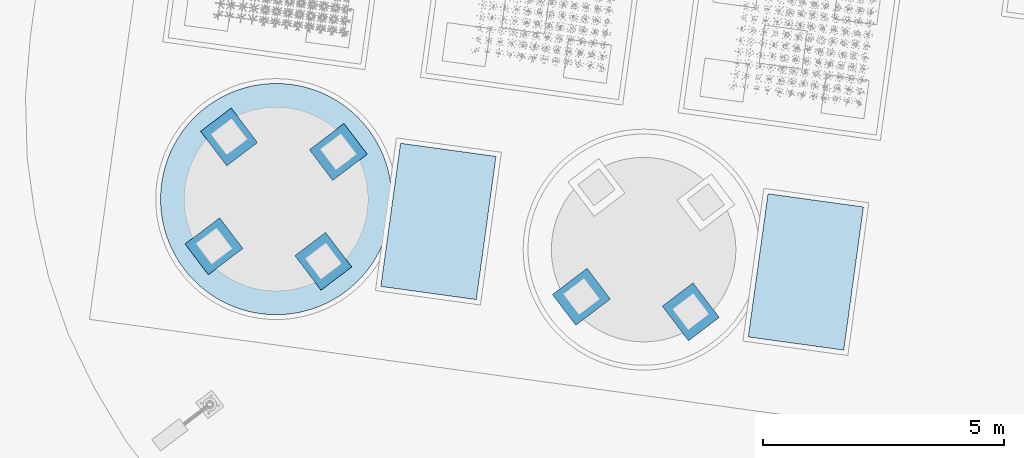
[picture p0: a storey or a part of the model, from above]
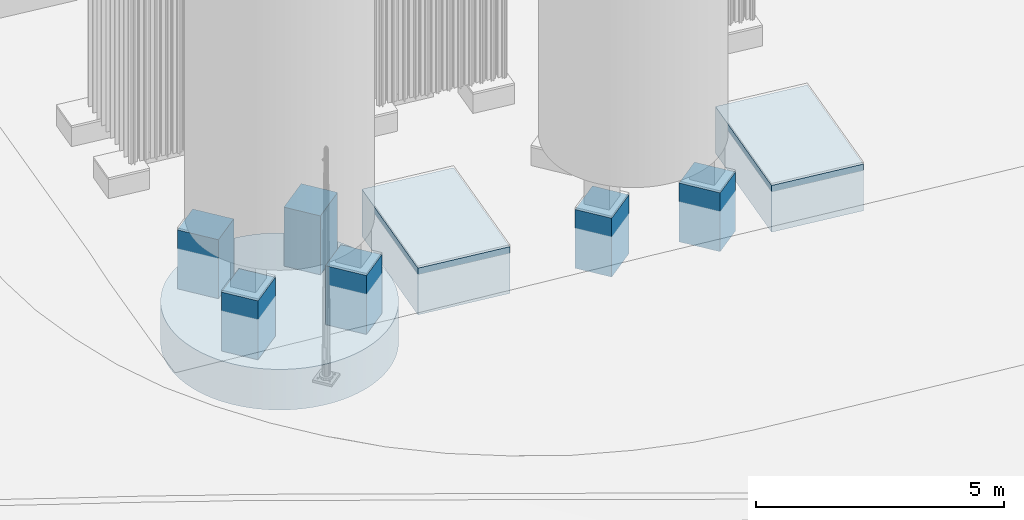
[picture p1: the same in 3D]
Properties of the parts of a building model (IFC4), part 108 of 134

# IfcSlab: Cimentación industrial (108)
Name | Material | Extensión de la malla en X (m) = ExtensionX (m) | Extensión de la malla en Y (m) = ExtensionY (m) | Extensión de la malla en Z (m) = ExtensionZ (m) = Espesor o altura real de sección (m) | Cota inferior de visualización (m) | Cota superior de visualización (m) | SuperficieDeLaMalla (m2) | VolumenGeometrico (m3) | JH_InformacionBIM, source = DocumentoFuente | material | dimensions | issues = IncidenciasPendientes | positioning = PosicionYEstado | assemblyId = Conjunto de cimentación | equipmentIds | supportPositionIds | sectionRef = Sección de referencia | sourceCadHandles | stableElementKey | geometryMetrics | materialAppearance | visualizationIdentity | appearance | Equipos asociados | Identificadores CAD de referencia | JH_Trazabilidad, Material = name | Cota inferior relativa (m) = Cota inferior relativa adoptada (m) | Cota superior relativa (m) = Cota superior relativa adoptada (m) | Área de planta (m²) | Volumen geométrico (m³) | Estado de la geometría | Acabado de visualización = Acabado | Identificador | status | JH_EvidenciaDeMaterial, source | Extensión local X (m) | Extensión local Y (m) | Perfil | ColorRGB | Rugosidad | Incidencias de origen
Cimentación de soporte de tuberías C07 · capa de limpieza | Hormigón de limpieza HA-20 | 1.35226 | 1.35226 | 0.1 | 285 | 285.1 | 3.36 | 0.144 | {"documentId":"LHD2609-JG00100-20260904","title":"Cimentaciones de equipos y pedestales del fabricante · revisión recibida 04/09/2026","date":"2026-09-04","sheet":"ZD1 / DZ-1","fileName":"LHD2609-JG00100_20260904.dwg","revisionCaveat":"Fecha de revisión tomada del nombre recibido; cajetines internos mantienen 02/07/2026 y algunos textos de plantilla.","sourceFileSha256":"b42eb027b7bc0b14c38d1d13514f4899b58a732aa8d0ba2ccf10fa2fc3192890"} | {"name":"Hormigón de limpieza HA-20","status":"documentado","source":"Secciones del fabricante: capa de limpieza de 100 mm; nota 2CED5"} | {"documented":[{"label":"Extensión local X","value":1.2,"unit":"m","source":"2CC5C, 2CD44, 2CC60, 2CC68, 2CC24, 2CC2B, 2CD69, 2CEAD, 2CE88","status":"derivada del contorno CAD"},{"label":"Extensión local Y","value":1.2,"unit":"m","source":"2CC5C, 2CD44, 2CC60, 2CC68, 2CC24, 2CC2B, 2CD69, 2CEAD, 2CE88","status":"derivada del contorno CAD"},{"label":"Cota inferior relativa adoptada","value":-1.1,"unit":"m","source":"ZD1 / DZ-1","status":"documentada"},{"label":"Cota superior relativa adoptada","value":-1.0,"unit":"m","source":"ZD1 / DZ-1","status":"documentada / separación por material"}],"geometry":[{"label":"Extensión de la malla en X","value":1.3522609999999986,"unit":"m","source":"Geometría releída del IFC; datum absoluto de proceso provisional","status":"derivado"},{"label":"Extensión de la malla en Y","value":1.352261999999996,"unit":"m","source":"Geometría releída del IFC; datum absoluto de proceso provisional","status":"derivado"},{"label":"Extensión de la malla en Z","value":0.1,"unit":"m","source":"Geometría releída del IFC; datum absoluto de proceso provisional","status":"derivado"},{"label":"Cota inferior de visualización","value":285.0,"unit":"m","source":"Geometría releída del IFC; datum absoluto de proceso provisional","status":"derivado"},{"label":"Cota superior de visualización","value":285.1,"unit":"m","source":"Geometría releída del IFC; datum absoluto de proceso provisional","status":"derivado"}]} | [] | {"Cota inferior relativa (m)":-1.1,"Cota superior relativa (m)":-1.0,"Cero absoluto de visualización (m)":286.1,"Estado del cero absoluto":"Provisional","Criterio":"Las cotas relativas proceden del dibujo; la equivalencia absoluta no está confirmada."} | SUP-C07 | [] | ["C07"] | ZD1 / DZ-1 | ["2CC5C","2CD44","2CC60","2CC68","2CC24","2CC2B","2CD69","2CEAD","2CE88"] | SUP-C07/Cimentación de soporte de tuberías C07 · capa de limpieza | {"boundingBoxM":{"min":[45.275149,74.127941,0.0],"max":[46.62741,75.480203,0.1]},"extentsM":[1.352261,1.352262,0.1],"meshSurfaceM2":3.359999,"meshVolumeM3":0.144,"closedSolid":true,"basis":"Magnitudes de las mallas representadas, no cantidades certificadas de obra, compra o fabricación. Las partes pueden compartir superficies; no se suman como un despiece de materiales."} | {"profileId":"concrete_ha20","name":"Hormigón de limpieza HA-20","materialName":"Hormigón de limpieza HA-20","physicalMaterialStatus":"documentado","physicalMaterialSource":"Secciones del fabricante: capa de limpieza de 100 mm; nota 2CED5","appearanceStatus":"criterio_visual","appearanceBasis":"Interpretación visual del material documental; el acabado, tono y parámetros PBR no son una especificación contractual.","note":"La apariencia gráfica no modifica ni confirma la especificación física del material."} | {"elementId":"found_0904_cc9eada5e0399d","ifcGuid":"3vSJTWcp9J8fS$usRsbQt$","ifcClass":"IfcSlab","buildingId":"process_plant","buildingName":"Zona de separación de aire","sourceDocumentId":"LHD2609-JG00100-20260904","sourceRepresentationKind":"foundation"} | {"profileId":"concrete_ha20","name":"Hormigón de limpieza HA-20","status":"criterio_visual","basis":"Interpretación visual del material documental; el acabado, tono y parámetros PBR no son una especificación contractual.","physicalMaterialUnchanged":true} |  | 2CC5C, 2CD44, 2CC60, 2CC68, 2CC24, 2CC2B, 2CD69, 2CEAD, 2CE88 | Hormigón de limpieza HA-20 | -1.1 | -1 | 1.44 | 0.144 | Contornos y sección documentados por el fabricante | Hormigón de limpieza HA-20 | found_0904_cc9eada5e0399d | documentado | Secciones del fabricante: capa de limpieza de 100 mm; nota 2CED5 | 1.2 | 1.2 | concrete_ha20 | [0.721569,0.709804,0.658824] | 0.98
Cimentación de soporte de tuberías C08 · capa de limpieza | Hormigón de limpieza HA-20 | 1.35226 | 1.35226 | 0.1 | 285 | 285.1 | 3.36 | 0.144 | {"documentId":"LHD2609-JG00100-20260904","title":"Cimentaciones de equipos y pedestales del fabricante · revisión recibida 04/09/2026","date":"2026-09-04","sheet":"ZD1 / DZ-1","fileName":"LHD2609-JG00100_20260904.dwg","revisionCaveat":"Fecha de revisión tomada del nombre recibido; cajetines internos mantienen 02/07/2026 y algunos textos de plantilla.","sourceFileSha256":"b42eb027b7bc0b14c38d1d13514f4899b58a732aa8d0ba2ccf10fa2fc3192890"} | {"name":"Hormigón de limpieza HA-20","status":"documentado","source":"Secciones del fabricante: capa de limpieza de 100 mm; nota 2CED5"} | {"documented":[{"label":"Extensión local X","value":1.2,"unit":"m","source":"2CC5D, 2CD45, 2CC61, 2CC69, 2CC25, 2CC2C, 2CD6A, 2CEAE, 2CE89","status":"derivada del contorno CAD"},{"label":"Extensión local Y","value":1.2,"unit":"m","source":"2CC5D, 2CD45, 2CC61, 2CC69, 2CC25, 2CC2C, 2CD6A, 2CEAE, 2CE89","status":"derivada del contorno CAD"},{"label":"Cota inferior relativa adoptada","value":-1.1,"unit":"m","source":"ZD1 / DZ-1","status":"documentada"},{"label":"Cota superior relativa adoptada","value":-1.0,"unit":"m","source":"ZD1 / DZ-1","status":"documentada / separación por material"}],"geometry":[{"label":"Extensión de la malla en X","value":1.3522609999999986,"unit":"m","source":"Geometría releída del IFC; datum absoluto de proceso provisional","status":"derivado"},{"label":"Extensión de la malla en Y","value":1.3522609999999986,"unit":"m","source":"Geometría releída del IFC; datum absoluto de proceso provisional","status":"derivado"},{"label":"Extensión de la malla en Z","value":0.1,"unit":"m","source":"Geometría releída del IFC; datum absoluto de proceso provisional","status":"derivado"},{"label":"Cota inferior de visualización","value":285.0,"unit":"m","source":"Geometría releída del IFC; datum absoluto de proceso provisional","status":"derivado"},{"label":"Cota superior de visualización","value":285.1,"unit":"m","source":"Geometría releída del IFC; datum absoluto de proceso provisional","status":"derivado"}]} | [] | {"Cota inferior relativa (m)":-1.1,"Cota superior relativa (m)":-1.0,"Cero absoluto de visualización (m)":286.1,"Estado del cero absoluto":"Provisional","Criterio":"Las cotas relativas proceden del dibujo; la equivalencia absoluta no está confirmada."} | SUP-C08 | [] | ["C08"] | ZD1 / DZ-1 | ["2CC5D","2CD45","2CC61","2CC69","2CC25","2CC2C","2CD6A","2CEAE","2CE89"] | SUP-C08/Cimentación de soporte de tuberías C08 · capa de limpieza | {"boundingBoxM":{"min":[46.414432,73.971307,0.0],"max":[47.766693,75.323568,0.1]},"extentsM":[1.352261,1.352261,0.1],"meshSurfaceM2":3.36,"meshVolumeM3":0.144,"closedSolid":true,"basis":"Magnitudes de las mallas representadas, no cantidades certificadas de obra, compra o fabricación. Las partes pueden compartir superficies; no se suman como un despiece de materiales."} | {"profileId":"concrete_ha20","name":"Hormigón de limpieza HA-20","materialName":"Hormigón de limpieza HA-20","physicalMaterialStatus":"documentado","physicalMaterialSource":"Secciones del fabricante: capa de limpieza de 100 mm; nota 2CED5","appearanceStatus":"criterio_visual","appearanceBasis":"Interpretación visual del material documental; el acabado, tono y parámetros PBR no son una especificación contractual.","note":"La apariencia gráfica no modifica ni confirma la especificación física del material."} | {"elementId":"found_0904_259d49ea950b82","ifcGuid":"1Fz0yCrrnRKgJ7DF1sHvFw","ifcClass":"IfcSlab","buildingId":"process_plant","buildingName":"Zona de separación de aire","sourceDocumentId":"LHD2609-JG00100-20260904","sourceRepresentationKind":"foundation"} | {"profileId":"concrete_ha20","name":"Hormigón de limpieza HA-20","status":"criterio_visual","basis":"Interpretación visual del material documental; el acabado, tono y parámetros PBR no son una especificación contractual.","physicalMaterialUnchanged":true} |  | 2CC5D, 2CD45, 2CC61, 2CC69, 2CC25, 2CC2C, 2CD6A, 2CEAE, 2CE89 | Hormigón de limpieza HA-20 | -1.1 | -1 | 1.44 | 0.144 | Contornos y sección documentados por el fabricante | Hormigón de limpieza HA-20 | found_0904_259d49ea950b82 | documentado | Secciones del fabricante: capa de limpieza de 100 mm; nota 2CED5 | 1.2 | 1.2 | concrete_ha20 | [0.721569,0.709804,0.658824] | 0.98
Cimentación de soporte de tuberías C09 · capa de limpieza | Hormigón de limpieza HA-20 | 1.35226 | 1.35226 | 0.1 | 285 | 285.1 | 3.36 | 0.144 | {"documentId":"LHD2609-JG00100-20260904","title":"Cimentaciones de equipos y pedestales del fabricante · revisión recibida 04/09/2026","date":"2026-09-04","sheet":"ZD1 / DZ-1","fileName":"LHD2609-JG00100_20260904.dwg","revisionCaveat":"Fecha de revisión tomada del nombre recibido; cajetines internos mantienen 02/07/2026 y algunos textos de plantilla.","sourceFileSha256":"b42eb027b7bc0b14c38d1d13514f4899b58a732aa8d0ba2ccf10fa2fc3192890"} | {"name":"Hormigón de limpieza HA-20","status":"documentado","source":"Secciones del fabricante: capa de limpieza de 100 mm; nota 2CED5"} | {"documented":[{"label":"Extensión local X","value":1.2,"unit":"m","source":"2CC5E, 2CD46, 2CDAA, 2CC6A, 2CC26, 2CC2D, 2CD6B, 2CEAF, 2CE8A","status":"derivada del contorno CAD"},{"label":"Extensión local Y","value":1.2,"unit":"m","source":"2CC5E, 2CD46, 2CDAA, 2CC6A, 2CC26, 2CC2D, 2CD6B, 2CEAF, 2CE8A","status":"derivada del contorno CAD"},{"label":"Cota inferior relativa adoptada","value":-1.1,"unit":"m","source":"ZD1 / DZ-1","status":"documentada"},{"label":"Cota superior relativa adoptada","value":-1.0,"unit":"m","source":"ZD1 / DZ-1","status":"documentada / separación por material"}],"geometry":[{"label":"Extensión de la malla en X","value":1.352261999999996,"unit":"m","source":"Geometría releída del IFC; datum absoluto de proceso provisional","status":"derivado"},{"label":"Extensión de la malla en Y","value":1.352261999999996,"unit":"m","source":"Geometría releída del IFC; datum absoluto de proceso provisional","status":"derivado"},{"label":"Extensión de la malla en Z","value":0.1,"unit":"m","source":"Geometría releída del IFC; datum absoluto de proceso provisional","status":"derivado"},{"label":"Cota inferior de visualización","value":285.0,"unit":"m","source":"Geometría releída del IFC; datum absoluto de proceso provisional","status":"derivado"},{"label":"Cota superior de visualización","value":285.1,"unit":"m","source":"Geometría releída del IFC; datum absoluto de proceso provisional","status":"derivado"}]} | [] | {"Cota inferior relativa (m)":-1.1,"Cota superior relativa (m)":-1.0,"Cero absoluto de visualización (m)":286.1,"Estado del cero absoluto":"Provisional","Criterio":"Las cotas relativas proceden del dibujo; la equivalencia absoluta no está confirmada."} | SUP-C09 | [] | ["C09"] | ZD1 / DZ-1 | ["2CC5E","2CD46","2CDAA","2CC6A","2CC26","2CC2D","2CD6B","2CEAF","2CE8A"] | SUP-C09/Cimentación de soporte de tuberías C09 · capa de limpieza | {"boundingBoxM":{"min":[44.594129,69.174537,0.0],"max":[45.946391,70.526799,0.1]},"extentsM":[1.352262,1.352262,0.1],"meshSurfaceM2":3.36,"meshVolumeM3":0.144,"closedSolid":true,"basis":"Magnitudes de las mallas representadas, no cantidades certificadas de obra, compra o fabricación. Las partes pueden compartir superficies; no se suman como un despiece de materiales."} | {"profileId":"concrete_ha20","name":"Hormigón de limpieza HA-20","materialName":"Hormigón de limpieza HA-20","physicalMaterialStatus":"documentado","physicalMaterialSource":"Secciones del fabricante: capa de limpieza de 100 mm; nota 2CED5","appearanceStatus":"criterio_visual","appearanceBasis":"Interpretación visual del material documental; el acabado, tono y parámetros PBR no son una especificación contractual.","note":"La apariencia gráfica no modifica ni confirma la especificación física del material."} | {"elementId":"found_0904_2cc7b8eef1ccfd","ifcGuid":"1x6CMRoZbNmwUsULRlYhuv","ifcClass":"IfcSlab","buildingId":"process_plant","buildingName":"Zona de separación de aire","sourceDocumentId":"LHD2609-JG00100-20260904","sourceRepresentationKind":"foundation"} | {"profileId":"concrete_ha20","name":"Hormigón de limpieza HA-20","status":"criterio_visual","basis":"Interpretación visual del material documental; el acabado, tono y parámetros PBR no son una especificación contractual.","physicalMaterialUnchanged":true} |  | 2CC5E, 2CD46, 2CDAA, 2CC6A, 2CC26, 2CC2D, 2CD6B, 2CEAF, 2CE8A | Hormigón de limpieza HA-20 | -1.1 | -1 | 1.44 | 0.144 | Contornos y sección documentados por el fabricante | Hormigón de limpieza HA-20 | found_0904_2cc7b8eef1ccfd | documentado | Secciones del fabricante: capa de limpieza de 100 mm; nota 2CED5 | 1.2 | 1.2 | concrete_ha20 | [0.721569,0.709804,0.658824] | 0.98
Cimentación de soporte de tuberías C10 · capa de limpieza | Hormigón de limpieza HA-20 | 1.35226 | 1.35226 | 0.1 | 285 | 285.1 | 3.36 | 0.144 | {"documentId":"LHD2609-JG00100-20260904","title":"Cimentaciones de equipos y pedestales del fabricante · revisión recibida 04/09/2026","date":"2026-09-04","sheet":"ZD1 / DZ-1","fileName":"LHD2609-JG00100_20260904.dwg","revisionCaveat":"Fecha de revisión tomada del nombre recibido; cajetines internos mantienen 02/07/2026 y algunos textos de plantilla.","sourceFileSha256":"b42eb027b7bc0b14c38d1d13514f4899b58a732aa8d0ba2ccf10fa2fc3192890"} | {"name":"Hormigón de limpieza HA-20","status":"documentado","source":"Secciones del fabricante: capa de limpieza de 100 mm; nota 2CED5"} | {"documented":[{"label":"Extensión local X","value":1.2,"unit":"m","source":"2CC5F, 2CD47, 2CDAB, 2CC6B, 2CC27, 2CC2E, 2CD6C, 2CEB0, 2CE8B","status":"derivada del contorno CAD"},{"label":"Extensión local Y","value":1.2,"unit":"m","source":"2CC5F, 2CD47, 2CDAB, 2CC6B, 2CC27, 2CC2E, 2CD6C, 2CEB0, 2CE8B","status":"derivada del contorno CAD"},{"label":"Cota inferior relativa adoptada","value":-1.1,"unit":"m","source":"ZD1 / DZ-1","status":"documentada"},{"label":"Cota superior relativa adoptada","value":-1.0,"unit":"m","source":"ZD1 / DZ-1","status":"documentada / separación por material"}],"geometry":[{"label":"Extensión de la malla en X","value":1.352261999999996,"unit":"m","source":"Geometría releída del IFC; datum absoluto de proceso provisional","status":"derivado"},{"label":"Extensión de la malla en Y","value":1.3522609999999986,"unit":"m","source":"Geometría releída del IFC; datum absoluto de proceso provisional","status":"derivado"},{"label":"Extensión de la malla en Z","value":0.1,"unit":"m","source":"Geometría releída del IFC; datum absoluto de proceso provisional","status":"derivado"},{"label":"Cota inferior de visualización","value":285.0,"unit":"m","source":"Geometría releída del IFC; datum absoluto de proceso provisional","status":"derivado"},{"label":"Cota superior de visualización","value":285.1,"unit":"m","source":"Geometría releída del IFC; datum absoluto de proceso provisional","status":"derivado"}]} | [] | {"Cota inferior relativa (m)":-1.1,"Cota superior relativa (m)":-1.0,"Cero absoluto de visualización (m)":286.1,"Estado del cero absoluto":"Provisional","Criterio":"Las cotas relativas proceden del dibujo; la equivalencia absoluta no está confirmada."} | SUP-C10 | [] | ["C10"] | ZD1 / DZ-1 | ["2CC5F","2CD47","2CDAB","2CC6B","2CC27","2CC2E","2CD6C","2CEB0","2CE8B"] | SUP-C10/Cimentación de soporte de tuberías C10 · capa de limpieza | {"boundingBoxM":{"min":[45.733412,69.017903,0.0],"max":[47.085674,70.370164,0.1]},"extentsM":[1.352262,1.352261,0.1],"meshSurfaceM2":3.36,"meshVolumeM3":0.144,"closedSolid":true,"basis":"Magnitudes de las mallas representadas, no cantidades certificadas de obra, compra o fabricación. Las partes pueden compartir superficies; no se suman como un despiece de materiales."} | {"profileId":"concrete_ha20","name":"Hormigón de limpieza HA-20","materialName":"Hormigón de limpieza HA-20","physicalMaterialStatus":"documentado","physicalMaterialSource":"Secciones del fabricante: capa de limpieza de 100 mm; nota 2CED5","appearanceStatus":"criterio_visual","appearanceBasis":"Interpretación visual del material documental; el acabado, tono y parámetros PBR no son una especificación contractual.","note":"La apariencia gráfica no modifica ni confirma la especificación física del material."} | {"elementId":"found_0904_6c0c38d0d3f0c8","ifcGuid":"0sXQR$utLGM8r3Y5FFjk_X","ifcClass":"IfcSlab","buildingId":"process_plant","buildingName":"Zona de separación de aire","sourceDocumentId":"LHD2609-JG00100-20260904","sourceRepresentationKind":"foundation"} | {"profileId":"concrete_ha20","name":"Hormigón de limpieza HA-20","status":"criterio_visual","basis":"Interpretación visual del material documental; el acabado, tono y parámetros PBR no son una especificación contractual.","physicalMaterialUnchanged":true} |  | 2CC5F, 2CD47, 2CDAB, 2CC6B, 2CC27, 2CC2E, 2CD6C, 2CEB0, 2CE8B | Hormigón de limpieza HA-20 | -1.1 | -1 | 1.44 | 0.144 | Contornos y sección documentados por el fabricante | Hormigón de limpieza HA-20 | found_0904_6c0c38d0d3f0c8 | documentado | Secciones del fabricante: capa de limpieza de 100 mm; nota 2CED5 | 1.2 | 1.2 | concrete_ha20 | [0.721569,0.709804,0.658824] | 0.98
Cimentación de soporte de tuberías C11 · capa de limpieza | Hormigón de limpieza HA-20 | 1.35226 | 1.35226 | 0.1 | 285 | 285.1 | 3.36 | 0.144 | {"documentId":"LHD2609-JG00100-20260904","title":"Cimentaciones de equipos y pedestales del fabricante · revisión recibida 04/09/2026","date":"2026-09-04","sheet":"ZD1 / DZ-1","fileName":"LHD2609-JG00100_20260904.dwg","revisionCaveat":"Fecha de revisión tomada del nombre recibido; cajetines internos mantienen 02/07/2026 y algunos textos de plantilla.","sourceFileSha256":"b42eb027b7bc0b14c38d1d13514f4899b58a732aa8d0ba2ccf10fa2fc3192890"} | {"name":"Hormigón de limpieza HA-20","status":"documentado","source":"Secciones del fabricante: capa de limpieza de 100 mm; nota 2CED5"} | {"documented":[{"label":"Extensión local X","value":1.2,"unit":"m","source":"2CC77, 2CD48, 2CDAC, 2CC78, 2CC73, 2CC74, 2CD6D, 2CEB1, 2CE8C","status":"derivada del contorno CAD"},{"label":"Extensión local Y","value":1.2,"unit":"m","source":"2CC77, 2CD48, 2CDAC, 2CC78, 2CC73, 2CC74, 2CD6D, 2CEB1, 2CE8C","status":"derivada del contorno CAD"},{"label":"Cota inferior relativa adoptada","value":-1.1,"unit":"m","source":"ZD1 / DZ-1","status":"documentada"},{"label":"Cota superior relativa adoptada","value":-1.0,"unit":"m","source":"ZD1 / DZ-1","status":"documentada / separación por material"}],"geometry":[{"label":"Extensión de la malla en X","value":1.3522609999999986,"unit":"m","source":"Geometría releída del IFC; datum absoluto de proceso provisional","status":"derivado"},{"label":"Extensión de la malla en Y","value":1.3522620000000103,"unit":"m","source":"Geometría releída del IFC; datum absoluto de proceso provisional","status":"derivado"},{"label":"Extensión de la malla en Z","value":0.1,"unit":"m","source":"Geometría releída del IFC; datum absoluto de proceso provisional","status":"derivado"},{"label":"Cota inferior de visualización","value":285.0,"unit":"m","source":"Geometría releída del IFC; datum absoluto de proceso provisional","status":"derivado"},{"label":"Cota superior de visualización","value":285.1,"unit":"m","source":"Geometría releída del IFC; datum absoluto de proceso provisional","status":"derivado"}]} | [] | {"Cota inferior relativa (m)":-1.1,"Cota superior relativa (m)":-1.0,"Cero absoluto de visualización (m)":286.1,"Estado del cero absoluto":"Provisional","Criterio":"Las cotas relativas proceden del dibujo; la equivalencia absoluta no está confirmada."} | SUP-C11 | [] | ["C11"] | ZD1 / DZ-1 | ["2CC77","2CD48","2CDAC","2CC78","2CC73","2CC74","2CD6D","2CEB1","2CE8C"] | SUP-C11/Cimentación de soporte de tuberías C11 · capa de limpieza | {"boundingBoxM":{"min":[43.91311,64.221133,0.0],"max":[45.265371,65.573395,0.1]},"extentsM":[1.352261,1.352262,0.1],"meshSurfaceM2":3.36,"meshVolumeM3":0.144,"closedSolid":true,"basis":"Magnitudes de las mallas representadas, no cantidades certificadas de obra, compra o fabricación. Las partes pueden compartir superficies; no se suman como un despiece de materiales."} | {"profileId":"concrete_ha20","name":"Hormigón de limpieza HA-20","materialName":"Hormigón de limpieza HA-20","physicalMaterialStatus":"documentado","physicalMaterialSource":"Secciones del fabricante: capa de limpieza de 100 mm; nota 2CED5","appearanceStatus":"criterio_visual","appearanceBasis":"Interpretación visual del material documental; el acabado, tono y parámetros PBR no son una especificación contractual.","note":"La apariencia gráfica no modifica ni confirma la especificación física del material."} | {"elementId":"found_0904_9a11c67a12d797","ifcGuid":"3vt4yr$LbKPAo0UQtqzgux","ifcClass":"IfcSlab","buildingId":"process_plant","buildingName":"Zona de separación de aire","sourceDocumentId":"LHD2609-JG00100-20260904","sourceRepresentationKind":"foundation"} | {"profileId":"concrete_ha20","name":"Hormigón de limpieza HA-20","status":"criterio_visual","basis":"Interpretación visual del material documental; el acabado, tono y parámetros PBR no son una especificación contractual.","physicalMaterialUnchanged":true} |  | 2CC77, 2CD48, 2CDAC, 2CC78, 2CC73, 2CC74, 2CD6D, 2CEB1, 2CE8C | Hormigón de limpieza HA-20 | -1.1 | -1 | 1.44 | 0.144 | Contornos y sección documentados por el fabricante | Hormigón de limpieza HA-20 | found_0904_9a11c67a12d797 | documentado | Secciones del fabricante: capa de limpieza de 100 mm; nota 2CED5 | 1.2 | 1.2 | concrete_ha20 | [0.721569,0.709804,0.658824] | 0.98
Cimentación de soporte de tuberías C12 · capa de limpieza | Hormigón de limpieza HA-20 | 1.35226 | 1.35226 | 0.1 | 285 | 285.1 | 3.36 | 0.144 | {"documentId":"LHD2609-JG00100-20260904","title":"Cimentaciones de equipos y pedestales del fabricante · revisión recibida 04/09/2026","date":"2026-09-04","sheet":"ZD1 / DZ-1","fileName":"LHD2609-JG00100_20260904.dwg","revisionCaveat":"Fecha de revisión tomada del nombre recibido; cajetines internos mantienen 02/07/2026 y algunos textos de plantilla.","sourceFileSha256":"b42eb027b7bc0b14c38d1d13514f4899b58a732aa8d0ba2ccf10fa2fc3192890"} | {"name":"Hormigón de limpieza HA-20","status":"documentado","source":"Secciones del fabricante: capa de limpieza de 100 mm; nota 2CED5"} | {"documented":[{"label":"Extensión local X","value":1.2,"unit":"m","source":"2CC7D, 2CD49, 2CDA8, 2CC7E, 2CC79, 2CC7A, 2CD6E, 2CEB2, 2CE8D","status":"derivada del contorno CAD"},{"label":"Extensión local Y","value":1.2,"unit":"m","source":"2CC7D, 2CD49, 2CDA8, 2CC7E, 2CC79, 2CC7A, 2CD6E, 2CEB2, 2CE8D","status":"derivada del contorno CAD"},{"label":"Cota inferior relativa adoptada","value":-1.1,"unit":"m","source":"ZD1 / DZ-1","status":"documentada"},{"label":"Cota superior relativa adoptada","value":-1.0,"unit":"m","source":"ZD1 / DZ-1","status":"documentada / separación por material"}],"geometry":[{"label":"Extensión de la malla en X","value":1.3522620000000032,"unit":"m","source":"Geometría releída del IFC; datum absoluto de proceso provisional","status":"derivado"},{"label":"Extensión de la malla en Y","value":1.3522609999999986,"unit":"m","source":"Geometría releída del IFC; datum absoluto de proceso provisional","status":"derivado"},{"label":"Extensión de la malla en Z","value":0.1,"unit":"m","source":"Geometría releída del IFC; datum absoluto de proceso provisional","status":"derivado"},{"label":"Cota inferior de visualización","value":285.0,"unit":"m","source":"Geometría releída del IFC; datum absoluto de proceso provisional","status":"derivado"},{"label":"Cota superior de visualización","value":285.1,"unit":"m","source":"Geometría releída del IFC; datum absoluto de proceso provisional","status":"derivado"}]} | [] | {"Cota inferior relativa (m)":-1.1,"Cota superior relativa (m)":-1.0,"Cero absoluto de visualización (m)":286.1,"Estado del cero absoluto":"Provisional","Criterio":"Las cotas relativas proceden del dibujo; la equivalencia absoluta no está confirmada."} | SUP-C12 | [] | ["C12"] | ZD1 / DZ-1 | ["2CC7D","2CD49","2CDA8","2CC7E","2CC79","2CC7A","2CD6E","2CEB2","2CE8D"] | SUP-C12/Cimentación de soporte de tuberías C12 · capa de limpieza | {"boundingBoxM":{"min":[45.052392,64.064499,0.0],"max":[46.404654,65.41676,0.1]},"extentsM":[1.352262,1.352261,0.1],"meshSurfaceM2":3.36,"meshVolumeM3":0.144,"closedSolid":true,"basis":"Magnitudes de las mallas representadas, no cantidades certificadas de obra, compra o fabricación. Las partes pueden compartir superficies; no se suman como un despiece de materiales."} | {"profileId":"concrete_ha20","name":"Hormigón de limpieza HA-20","materialName":"Hormigón de limpieza HA-20","physicalMaterialStatus":"documentado","physicalMaterialSource":"Secciones del fabricante: capa de limpieza de 100 mm; nota 2CED5","appearanceStatus":"criterio_visual","appearanceBasis":"Interpretación visual del material documental; el acabado, tono y parámetros PBR no son una especificación contractual.","note":"La apariencia gráfica no modifica ni confirma la especificación física del material."} | {"elementId":"found_0904_6abf42ab301af1","ifcGuid":"3Ao5pmfOPG8wUEm4Oe6gOX","ifcClass":"IfcSlab","buildingId":"process_plant","buildingName":"Zona de separación de aire","sourceDocumentId":"LHD2609-JG00100-20260904","sourceRepresentationKind":"foundation"} | {"profileId":"concrete_ha20","name":"Hormigón de limpieza HA-20","status":"criterio_visual","basis":"Interpretación visual del material documental; el acabado, tono y parámetros PBR no son una especificación contractual.","physicalMaterialUnchanged":true} |  | 2CC7D, 2CD49, 2CDA8, 2CC7E, 2CC79, 2CC7A, 2CD6E, 2CEB2, 2CE8D | Hormigón de limpieza HA-20 | -1.1 | -1 | 1.44 | 0.144 | Contornos y sección documentados por el fabricante | Hormigón de limpieza HA-20 | found_0904_6abf42ab301af1 | documentado | Secciones del fabricante: capa de limpieza de 100 mm; nota 2CED5 | 1.2 | 1.2 | concrete_ha20 | [0.721569,0.709804,0.658824] | 0.98
Cimentación de soporte de tuberías C13 · capa de limpieza | Hormigón de limpieza HA-20 | 1.35226 | 1.35226 | 0.1 | 285 | 285.1 | 3.36 | 0.144 | {"documentId":"LHD2609-JG00100-20260904","title":"Cimentaciones de equipos y pedestales del fabricante · revisión recibida 04/09/2026","date":"2026-09-04","sheet":"ZD1 / DZ-1","fileName":"LHD2609-JG00100_20260904.dwg","revisionCaveat":"Fecha de revisión tomada del nombre recibido; cajetines internos mantienen 02/07/2026 y algunos textos de plantilla.","sourceFileSha256":"b42eb027b7bc0b14c38d1d13514f4899b58a732aa8d0ba2ccf10fa2fc3192890"} | {"name":"Hormigón de limpieza HA-20","status":"documentado","source":"Secciones del fabricante: capa de limpieza de 100 mm; nota 2CED5"} | {"documented":[{"label":"Extensión local X","value":1.2,"unit":"m","source":"2CC83, 2CD4A, 2CDA9, 2CC84, 2CC7F, 2CC80, 2CD6F, 2CEB3, 2CE8E","status":"derivada del contorno CAD"},{"label":"Extensión local Y","value":1.2,"unit":"m","source":"2CC83, 2CD4A, 2CDA9, 2CC84, 2CC7F, 2CC80, 2CD6F, 2CEB3, 2CE8E","status":"derivada del contorno CAD"},{"label":"Cota inferior relativa adoptada","value":-1.1,"unit":"m","source":"ZD1 / DZ-1","status":"documentada"},{"label":"Cota superior relativa adoptada","value":-1.0,"unit":"m","source":"ZD1 / DZ-1","status":"documentada / separación por material"}],"geometry":[{"label":"Extensión de la malla en X","value":1.352261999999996,"unit":"m","source":"Geometría releída del IFC; datum absoluto de proceso provisional","status":"derivado"},{"label":"Extensión de la malla en Y","value":1.3522610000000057,"unit":"m","source":"Geometría releída del IFC; datum absoluto de proceso provisional","status":"derivado"},{"label":"Extensión de la malla en Z","value":0.1,"unit":"m","source":"Geometría releída del IFC; datum absoluto de proceso provisional","status":"derivado"},{"label":"Cota inferior de visualización","value":285.0,"unit":"m","source":"Geometría releída del IFC; datum absoluto de proceso provisional","status":"derivado"},{"label":"Cota superior de visualización","value":285.1,"unit":"m","source":"Geometría releída del IFC; datum absoluto de proceso provisional","status":"derivado"}]} | [] | {"Cota inferior relativa (m)":-1.1,"Cota superior relativa (m)":-1.0,"Cero absoluto de visualización (m)":286.1,"Estado del cero absoluto":"Provisional","Criterio":"Las cotas relativas proceden del dibujo; la equivalencia absoluta no está confirmada."} | SUP-C13 | [] | ["C13"] | ZD1 / DZ-1 | ["2CC83","2CD4A","2CDA9","2CC84","2CC7F","2CC80","2CD6F","2CEB3","2CE8E"] | SUP-C13/Cimentación de soporte de tuberías C13 · capa de limpieza | {"boundingBoxM":{"min":[43.163988,58.772389,0.0],"max":[44.51625,60.12465,0.1]},"extentsM":[1.352262,1.352261,0.1],"meshSurfaceM2":3.36,"meshVolumeM3":0.144,"closedSolid":true,"basis":"Magnitudes de las mallas representadas, no cantidades certificadas de obra, compra o fabricación. Las partes pueden compartir superficies; no se suman como un despiece de materiales."} | {"profileId":"concrete_ha20","name":"Hormigón de limpieza HA-20","materialName":"Hormigón de limpieza HA-20","physicalMaterialStatus":"documentado","physicalMaterialSource":"Secciones del fabricante: capa de limpieza de 100 mm; nota 2CED5","appearanceStatus":"criterio_visual","appearanceBasis":"Interpretación visual del material documental; el acabado, tono y parámetros PBR no son una especificación contractual.","note":"La apariencia gráfica no modifica ni confirma la especificación física del material."} | {"elementId":"found_0904_ab60e9a844fe34","ifcGuid":"2fRnzw3fLUoQRttIkc$DoH","ifcClass":"IfcSlab","buildingId":"process_plant","buildingName":"Zona de separación de aire","sourceDocumentId":"LHD2609-JG00100-20260904","sourceRepresentationKind":"foundation"} | {"profileId":"concrete_ha20","name":"Hormigón de limpieza HA-20","status":"criterio_visual","basis":"Interpretación visual del material documental; el acabado, tono y parámetros PBR no son una especificación contractual.","physicalMaterialUnchanged":true} |  | 2CC83, 2CD4A, 2CDA9, 2CC84, 2CC7F, 2CC80, 2CD6F, 2CEB3, 2CE8E | Hormigón de limpieza HA-20 | -1.1 | -1 | 1.44 | 0.144 | Contornos y sección documentados por el fabricante | Hormigón de limpieza HA-20 | found_0904_ab60e9a844fe34 | documentado | Secciones del fabricante: capa de limpieza de 100 mm; nota 2CED5 | 1.2 | 1.2 | concrete_ha20 | [0.721569,0.709804,0.658824] | 0.98
Cimentación de soporte de tuberías C14 · capa de limpieza | Hormigón de limpieza HA-20 | 1.35226 | 1.35226 | 0.1 | 285 | 285.1 | 3.36 | 0.144 | {"documentId":"LHD2609-JG00100-20260904","title":"Cimentaciones de equipos y pedestales del fabricante · revisión recibida 04/09/2026","date":"2026-09-04","sheet":"ZD1 / DZ-1","fileName":"LHD2609-JG00100_20260904.dwg","revisionCaveat":"Fecha de revisión tomada del nombre recibido; cajetines internos mantienen 02/07/2026 y algunos textos de plantilla.","sourceFileSha256":"b42eb027b7bc0b14c38d1d13514f4899b58a732aa8d0ba2ccf10fa2fc3192890"} | {"name":"Hormigón de limpieza HA-20","status":"documentado","source":"Secciones del fabricante: capa de limpieza de 100 mm; nota 2CED5"} | {"documented":[{"label":"Extensión local X","value":1.2,"unit":"m","source":"2CC89, 2CD4B, 2CDA7, 2CC8A, 2CC85, 2CC86, 2CD70, 2CEB4, 2CE8F","status":"derivada del contorno CAD"},{"label":"Extensión local Y","value":1.2,"unit":"m","source":"2CC89, 2CD4B, 2CDA7, 2CC8A, 2CC85, 2CC86, 2CD70, 2CEB4, 2CE8F","status":"derivada del contorno CAD"},{"label":"Cota inferior relativa adoptada","value":-1.1,"unit":"m","source":"ZD1 / DZ-1","status":"documentada"},{"label":"Cota superior relativa adoptada","value":-1.0,"unit":"m","source":"ZD1 / DZ-1","status":"documentada / separación por material"}],"geometry":[{"label":"Extensión de la malla en X","value":1.352261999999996,"unit":"m","source":"Geometría releída del IFC; datum absoluto de proceso provisional","status":"derivado"},{"label":"Extensión de la malla en Y","value":1.352261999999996,"unit":"m","source":"Geometría releída del IFC; datum absoluto de proceso provisional","status":"derivado"},{"label":"Extensión de la malla en Z","value":0.1,"unit":"m","source":"Geometría releída del IFC; datum absoluto de proceso provisional","status":"derivado"},{"label":"Cota inferior de visualización","value":285.0,"unit":"m","source":"Geometría releída del IFC; datum absoluto de proceso provisional","status":"derivado"},{"label":"Cota superior de visualización","value":285.1,"unit":"m","source":"Geometría releída del IFC; datum absoluto de proceso provisional","status":"derivado"}]} | [] | {"Cota inferior relativa (m)":-1.1,"Cota superior relativa (m)":-1.0,"Cero absoluto de visualización (m)":286.1,"Estado del cero absoluto":"Provisional","Criterio":"Las cotas relativas proceden del dibujo; la equivalencia absoluta no está confirmada."} | SUP-C14 | [] | ["C14"] | ZD1 / DZ-1 | ["2CC89","2CD4B","2CDA7","2CC8A","2CC85","2CC86","2CD70","2CEB4","2CE8F"] | SUP-C14/Cimentación de soporte de tuberías C14 · capa de limpieza | {"boundingBoxM":{"min":[44.303271,58.615754,0.0],"max":[45.655533,59.968016,0.1]},"extentsM":[1.352262,1.352262,0.1],"meshSurfaceM2":3.36,"meshVolumeM3":0.144,"closedSolid":true,"basis":"Magnitudes de las mallas representadas, no cantidades certificadas de obra, compra o fabricación. Las partes pueden compartir superficies; no se suman como un despiece de materiales."} | {"profileId":"concrete_ha20","name":"Hormigón de limpieza HA-20","materialName":"Hormigón de limpieza HA-20","physicalMaterialStatus":"documentado","physicalMaterialSource":"Secciones del fabricante: capa de limpieza de 100 mm; nota 2CED5","appearanceStatus":"criterio_visual","appearanceBasis":"Interpretación visual del material documental; el acabado, tono y parámetros PBR no son una especificación contractual.","note":"La apariencia gráfica no modifica ni confirma la especificación física del material."} | {"elementId":"found_0904_732f7a826d1871","ifcGuid":"1qV9CKczXUswzFjCi6jaVq","ifcClass":"IfcSlab","buildingId":"process_plant","buildingName":"Zona de separación de aire","sourceDocumentId":"LHD2609-JG00100-20260904","sourceRepresentationKind":"foundation"} | {"profileId":"concrete_ha20","name":"Hormigón de limpieza HA-20","status":"criterio_visual","basis":"Interpretación visual del material documental; el acabado, tono y parámetros PBR no son una especificación contractual.","physicalMaterialUnchanged":true} |  | 2CC89, 2CD4B, 2CDA7, 2CC8A, 2CC85, 2CC86, 2CD70, 2CEB4, 2CE8F | Hormigón de limpieza HA-20 | -1.1 | -1 | 1.44 | 0.144 | Contornos y sección documentados por el fabricante | Hormigón de limpieza HA-20 | found_0904_732f7a826d1871 | documentado | Secciones del fabricante: capa de limpieza de 100 mm; nota 2CED5 | 1.2 | 1.2 | concrete_ha20 | [0.721569,0.709804,0.658824] | 0.98
Cimentación de marquesina C15 · capa de limpieza | Hormigón de limpieza HA-20 | 1.46495 | 1.46495 | 0.1 | 284.5 | 284.6 | 3.9 | 0.169 | {"documentId":"LHD2609-JG00100-20260904","title":"Cimentaciones de equipos y pedestales del fabricante · revisión recibida 04/09/2026","date":"2026-09-04","sheet":"JC1 / DZ","fileName":"LHD2609-JG00100_20260904.dwg","revisionCaveat":"Fecha de revisión tomada del nombre recibido; cajetines internos mantienen 02/07/2026 y algunos textos de plantilla.","sourceFileSha256":"b42eb027b7bc0b14c38d1d13514f4899b58a732aa8d0ba2ccf10fa2fc3192890"} | {"name":"Hormigón de limpieza HA-20","status":"documentado","source":"Secciones del fabricante: capa de limpieza de 100 mm; nota 2CED5"} | {"documented":[{"label":"Extensión local X","value":1.3,"unit":"m","source":"2CC9F, 2CD4C, 2CCBE, 2CD8C, 2CCB0, 2CCB1, 2CD71, 2CEF2, 2CEF1","status":"derivada del contorno CAD"},{"label":"Extensión local Y","value":1.3,"unit":"m","source":"2CC9F, 2CD4C, 2CCBE, 2CD8C, 2CCB0, 2CCB1, 2CD71, 2CEF2, 2CEF1","status":"derivada del contorno CAD"},{"label":"Cota inferior relativa adoptada","value":-1.6,"unit":"m","source":"JC1 / DZ","status":"documentada"},{"label":"Cota superior relativa adoptada","value":-1.5,"unit":"m","source":"JC1 / DZ","status":"documentada / separación por material"}],"geometry":[{"label":"Extensión de la malla en X","value":1.4649500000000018,"unit":"m","source":"Geometría releída del IFC; datum absoluto de proceso provisional","status":"derivado"},{"label":"Extensión de la malla en Y","value":1.4649499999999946,"unit":"m","source":"Geometría releída del IFC; datum absoluto de proceso provisional","status":"derivado"},{"label":"Extensión de la malla en Z","value":0.09999999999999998,"unit":"m","source":"Geometría releída del IFC; datum absoluto de proceso provisional","status":"derivado"},{"label":"Cota inferior de visualización","value":284.5,"unit":"m","source":"Geometría releída del IFC; datum absoluto de proceso provisional","status":"derivado"},{"label":"Cota superior de visualización","value":284.6,"unit":"m","source":"Geometría releída del IFC; datum absoluto de proceso provisional","status":"derivado"}]} | [] | {"Cota inferior relativa (m)":-1.6,"Cota superior relativa (m)":-1.5,"Cero absoluto de visualización (m)":286.1,"Estado del cero absoluto":"Provisional","Criterio":"Las cotas relativas proceden del dibujo; la equivalencia absoluta no está confirmada."} | SUP-C15 | [] | ["C15"] | JC1 / DZ | ["2CC9F","2CD4C","2CCBE","2CD8C","2CCB0","2CCB1","2CD71","2CEF2","2CEF1"] | SUP-C15/Cimentación de marquesina C15 · capa de limpieza | {"boundingBoxM":{"min":[36.285596,57.736102,-0.5],"max":[37.750546,59.201052,-0.4]},"extentsM":[1.46495,1.46495,0.1],"meshSurfaceM2":3.9,"meshVolumeM3":0.169,"closedSolid":true,"basis":"Magnitudes de las mallas representadas, no cantidades certificadas de obra, compra o fabricación. Las partes pueden compartir superficies; no se suman como un despiece de materiales."} | {"profileId":"concrete_ha20","name":"Hormigón de limpieza HA-20","materialName":"Hormigón de limpieza HA-20","physicalMaterialStatus":"documentado","physicalMaterialSource":"Secciones del fabricante: capa de limpieza de 100 mm; nota 2CED5","appearanceStatus":"criterio_visual","appearanceBasis":"Interpretación visual del material documental; el acabado, tono y parámetros PBR no son una especificación contractual.","note":"La apariencia gráfica no modifica ni confirma la especificación física del material."} | {"elementId":"found_0904_354c355a2ca4ac","ifcGuid":"1UwEnpueTUUP2KRTjLtAW$","ifcClass":"IfcSlab","buildingId":"process_plant","buildingName":"Zona de separación de aire","sourceDocumentId":"LHD2609-JG00100-20260904","sourceRepresentationKind":"foundation"} | {"profileId":"concrete_ha20","name":"Hormigón de limpieza HA-20","status":"criterio_visual","basis":"Interpretación visual del material documental; el acabado, tono y parámetros PBR no son una especificación contractual.","physicalMaterialUnchanged":true} |  | 2CC9F, 2CD4C, 2CCBE, 2CD8C, 2CCB0, 2CCB1, 2CD71, 2CEF2, 2CEF1 | Hormigón de limpieza HA-20 | -1.6 | -1.5 | 1.69 | 0.169 | Contornos y sección documentados por el fabricante | Hormigón de limpieza HA-20 | found_0904_354c355a2ca4ac | documentado | Secciones del fabricante: capa de limpieza de 100 mm; nota 2CED5 | 1.3 | 1.3 | concrete_ha20 | [0.721569,0.709804,0.658824] | 0.98
Cimentación de marquesina C16 · capa de limpieza | Hormigón de limpieza HA-20 | 1.46495 | 1.46495 | 0.1 | 284.5 | 284.6 | 3.9 | 0.169 | {"documentId":"LHD2609-JG00100-20260904","title":"Cimentaciones de equipos y pedestales del fabricante · revisión recibida 04/09/2026","date":"2026-09-04","sheet":"JC1 / DZ","fileName":"LHD2609-JG00100_20260904.dwg","revisionCaveat":"Fecha de revisión tomada del nombre recibido; cajetines internos mantienen 02/07/2026 y algunos textos de plantilla.","sourceFileSha256":"b42eb027b7bc0b14c38d1d13514f4899b58a732aa8d0ba2ccf10fa2fc3192890"} | {"name":"Hormigón de limpieza HA-20","status":"documentado","source":"Secciones del fabricante: capa de limpieza de 100 mm; nota 2CED5"} | {"documented":[{"label":"Extensión local X","value":1.3,"unit":"m","source":"2CCA0, 2CD4D, 2CCBF, 2CD8D, 2CCAE, 2CCAF, 2CD72, 2CEF4, 2CEF3","status":"derivada del contorno CAD"},{"label":"Extensión local Y","value":1.3,"unit":"m","source":"2CCA0, 2CD4D, 2CCBF, 2CD8D, 2CCAE, 2CCAF, 2CD72, 2CEF4, 2CEF3","status":"derivada del contorno CAD"},{"label":"Cota inferior relativa adoptada","value":-1.6,"unit":"m","source":"JC1 / DZ","status":"documentada"},{"label":"Cota superior relativa adoptada","value":-1.5,"unit":"m","source":"JC1 / DZ","status":"documentada / separación por material"}],"geometry":[{"label":"Extensión de la malla en X","value":1.4649500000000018,"unit":"m","source":"Geometría releída del IFC; datum absoluto de proceso provisional","status":"derivado"},{"label":"Extensión de la malla en Y","value":1.4649500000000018,"unit":"m","source":"Geometría releída del IFC; datum absoluto de proceso provisional","status":"derivado"},{"label":"Extensión de la malla en Z","value":0.09999999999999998,"unit":"m","source":"Geometría releída del IFC; datum absoluto de proceso provisional","status":"derivado"},{"label":"Cota inferior de visualización","value":284.5,"unit":"m","source":"Geometría releída del IFC; datum absoluto de proceso provisional","status":"derivado"},{"label":"Cota superior de visualización","value":284.6,"unit":"m","source":"Geometría releída del IFC; datum absoluto de proceso provisional","status":"derivado"}]} | [] | {"Cota inferior relativa (m)":-1.6,"Cota superior relativa (m)":-1.5,"Cero absoluto de visualización (m)":286.1,"Estado del cero absoluto":"Provisional","Criterio":"Las cotas relativas proceden del dibujo; la equivalencia absoluta no está confirmada."} | SUP-C16 | [] | ["C16"] | JC1 / DZ | ["2CCA0","2CD4D","2CCBF","2CD8D","2CCAE","2CCAF","2CD72","2CEF4","2CEF3"] | SUP-C16/Cimentación de marquesina C16 · capa de limpieza | {"boundingBoxM":{"min":[35.931466,55.160332,-0.5],"max":[37.396416,56.625282,-0.4]},"extentsM":[1.46495,1.46495,0.1],"meshSurfaceM2":3.9,"meshVolumeM3":0.169,"closedSolid":true,"basis":"Magnitudes de las mallas representadas, no cantidades certificadas de obra, compra o fabricación. Las partes pueden compartir superficies; no se suman como un despiece de materiales."} | {"profileId":"concrete_ha20","name":"Hormigón de limpieza HA-20","materialName":"Hormigón de limpieza HA-20","physicalMaterialStatus":"documentado","physicalMaterialSource":"Secciones del fabricante: capa de limpieza de 100 mm; nota 2CED5","appearanceStatus":"criterio_visual","appearanceBasis":"Interpretación visual del material documental; el acabado, tono y parámetros PBR no son una especificación contractual.","note":"La apariencia gráfica no modifica ni confirma la especificación física del material."} | {"elementId":"found_0904_4a62e3ef3a2717","ifcGuid":"0qTDv88hfHjhLyzdwCnyfL","ifcClass":"IfcSlab","buildingId":"process_plant","buildingName":"Zona de separación de aire","sourceDocumentId":"LHD2609-JG00100-20260904","sourceRepresentationKind":"foundation"} | {"profileId":"concrete_ha20","name":"Hormigón de limpieza HA-20","status":"criterio_visual","basis":"Interpretación visual del material documental; el acabado, tono y parámetros PBR no son una especificación contractual.","physicalMaterialUnchanged":true} |  | 2CCA0, 2CD4D, 2CCBF, 2CD8D, 2CCAE, 2CCAF, 2CD72, 2CEF4, 2CEF3 | Hormigón de limpieza HA-20 | -1.6 | -1.5 | 1.69 | 0.169 | Contornos y sección documentados por el fabricante | Hormigón de limpieza HA-20 | found_0904_4a62e3ef3a2717 | documentado | Secciones del fabricante: capa de limpieza de 100 mm; nota 2CED5 | 1.3 | 1.3 | concrete_ha20 | [0.721569,0.709804,0.658824] | 0.98
Cimentación de marquesina C17 · capa de limpieza | Hormigón de limpieza HA-20 | 1.46495 | 1.46495 | 0.1 | 284.5 | 284.6 | 3.9 | 0.169 | {"documentId":"LHD2609-JG00100-20260904","title":"Cimentaciones de equipos y pedestales del fabricante · revisión recibida 04/09/2026","date":"2026-09-04","sheet":"JC1 / DZ","fileName":"LHD2609-JG00100_20260904.dwg","revisionCaveat":"Fecha de revisión tomada del nombre recibido; cajetines internos mantienen 02/07/2026 y algunos textos de plantilla.","sourceFileSha256":"b42eb027b7bc0b14c38d1d13514f4899b58a732aa8d0ba2ccf10fa2fc3192890"} | {"name":"Hormigón de limpieza HA-20","status":"documentado","source":"Secciones del fabricante: capa de limpieza de 100 mm; nota 2CED5"} | {"documented":[{"label":"Extensión local X","value":1.3,"unit":"m","source":"2CCA1, 2CD4E, 2CCC0, 2CD8E, 2CCAB, 2CCAC, 2CD73, 2CEF6, 2CEF5","status":"derivada del contorno CAD"},{"label":"Extensión local Y","value":1.3,"unit":"m","source":"2CCA1, 2CD4E, 2CCC0, 2CD8E, 2CCAB, 2CCAC, 2CD73, 2CEF6, 2CEF5","status":"derivada del contorno CAD"},{"label":"Cota inferior relativa adoptada","value":-1.6,"unit":"m","source":"JC1 / DZ","status":"documentada"},{"label":"Cota superior relativa adoptada","value":-1.5,"unit":"m","source":"JC1 / DZ","status":"documentada / separación por material"}],"geometry":[{"label":"Extensión de la malla en X","value":1.4649499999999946,"unit":"m","source":"Geometría releída del IFC; datum absoluto de proceso provisional","status":"derivado"},{"label":"Extensión de la malla en Y","value":1.4649500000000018,"unit":"m","source":"Geometría releída del IFC; datum absoluto de proceso provisional","status":"derivado"},{"label":"Extensión de la malla en Z","value":0.09999999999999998,"unit":"m","source":"Geometría releída del IFC; datum absoluto de proceso provisional","status":"derivado"},{"label":"Cota inferior de visualización","value":284.5,"unit":"m","source":"Geometría releída del IFC; datum absoluto de proceso provisional","status":"derivado"},{"label":"Cota superior de visualización","value":284.6,"unit":"m","source":"Geometría releída del IFC; datum absoluto de proceso provisional","status":"derivado"}]} | [] | {"Cota inferior relativa (m)":-1.6,"Cota superior relativa (m)":-1.5,"Cero absoluto de visualización (m)":286.1,"Estado del cero absoluto":"Provisional","Criterio":"Las cotas relativas proceden del dibujo; la equivalencia absoluta no está confirmada."} | SUP-C17 | [] | ["C17"] | JC1 / DZ | ["2CCA1","2CD4E","2CCC0","2CD8E","2CCAB","2CCAC","2CD73","2CEF6","2CEF5"] | SUP-C17/Cimentación de marquesina C17 · capa de limpieza | {"boundingBoxM":{"min":[42.081079,56.939309,-0.5],"max":[43.546029,58.404259,-0.4]},"extentsM":[1.46495,1.46495,0.1],"meshSurfaceM2":3.9,"meshVolumeM3":0.169,"closedSolid":true,"basis":"Magnitudes de las mallas representadas, no cantidades certificadas de obra, compra o fabricación. Las partes pueden compartir superficies; no se suman como un despiece de materiales."} | {"profileId":"concrete_ha20","name":"Hormigón de limpieza HA-20","materialName":"Hormigón de limpieza HA-20","physicalMaterialStatus":"documentado","physicalMaterialSource":"Secciones del fabricante: capa de limpieza de 100 mm; nota 2CED5","appearanceStatus":"criterio_visual","appearanceBasis":"Interpretación visual del material documental; el acabado, tono y parámetros PBR no son una especificación contractual.","note":"La apariencia gráfica no modifica ni confirma la especificación física del material."} | {"elementId":"found_0904_b2f60b3c0f0241","ifcGuid":"1rzSUDZg1O9BVHdqKstZni","ifcClass":"IfcSlab","buildingId":"process_plant","buildingName":"Zona de separación de aire","sourceDocumentId":"LHD2609-JG00100-20260904","sourceRepresentationKind":"foundation"} | {"profileId":"concrete_ha20","name":"Hormigón de limpieza HA-20","status":"criterio_visual","basis":"Interpretación visual del material documental; el acabado, tono y parámetros PBR no son una especificación contractual.","physicalMaterialUnchanged":true} |  | 2CCA1, 2CD4E, 2CCC0, 2CD8E, 2CCAB, 2CCAC, 2CD73, 2CEF6, 2CEF5 | Hormigón de limpieza HA-20 | -1.6 | -1.5 | 1.69 | 0.169 | Contornos y sección documentados por el fabricante | Hormigón de limpieza HA-20 | found_0904_b2f60b3c0f0241 | documentado | Secciones del fabricante: capa de limpieza de 100 mm; nota 2CED5 | 1.3 | 1.3 | concrete_ha20 | [0.721569,0.709804,0.658824] | 0.98
Cimentación de marquesina C18 · capa de limpieza | Hormigón de limpieza HA-20 | 1.46495 | 1.46495 | 0.1 | 284.5 | 284.6 | 3.9 | 0.169 | {"documentId":"LHD2609-JG00100-20260904","title":"Cimentaciones de equipos y pedestales del fabricante · revisión recibida 04/09/2026","date":"2026-09-04","sheet":"JC1 / DZ","fileName":"LHD2609-JG00100_20260904.dwg","revisionCaveat":"Fecha de revisión tomada del nombre recibido; cajetines internos mantienen 02/07/2026 y algunos textos de plantilla.","sourceFileSha256":"b42eb027b7bc0b14c38d1d13514f4899b58a732aa8d0ba2ccf10fa2fc3192890"} | {"name":"Hormigón de limpieza HA-20","status":"documentado","source":"Secciones del fabricante: capa de limpieza de 100 mm; nota 2CED5"} | {"documented":[{"label":"Extensión local X","value":1.3,"unit":"m","source":"2CCA2, 2CD4F, 2CCC1, 2CD8F, 2CCAA, 2CCAD, 2CD74, 2CEF8, 2CEF7","status":"derivada del contorno CAD"},{"label":"Extensión local Y","value":1.3,"unit":"m","source":"2CCA2, 2CD4F, 2CCC1, 2CD8F, 2CCAA, 2CCAD, 2CD74, 2CEF8, 2CEF7","status":"derivada del contorno CAD"},{"label":"Cota inferior relativa adoptada","value":-1.6,"unit":"m","source":"JC1 / DZ","status":"documentada"},{"label":"Cota superior relativa adoptada","value":-1.5,"unit":"m","source":"JC1 / DZ","status":"documentada / separación por material"}],"geometry":[{"label":"Extensión de la malla en X","value":1.4649509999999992,"unit":"m","source":"Geometría releída del IFC; datum absoluto de proceso provisional","status":"derivado"},{"label":"Extensión de la malla en Y","value":1.4649499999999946,"unit":"m","source":"Geometría releída del IFC; datum absoluto de proceso provisional","status":"derivado"},{"label":"Extensión de la malla en Z","value":0.09999999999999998,"unit":"m","source":"Geometría releída del IFC; datum absoluto de proceso provisional","status":"derivado"},{"label":"Cota inferior de visualización","value":284.5,"unit":"m","source":"Geometría releída del IFC; datum absoluto de proceso provisional","status":"derivado"},{"label":"Cota superior de visualización","value":284.6,"unit":"m","source":"Geometría releída del IFC; datum absoluto de proceso provisional","status":"derivado"}]} | [] | {"Cota inferior relativa (m)":-1.6,"Cota superior relativa (m)":-1.5,"Cero absoluto de visualización (m)":286.1,"Estado del cero absoluto":"Provisional","Criterio":"Las cotas relativas proceden del dibujo; la equivalencia absoluta no está confirmada."} | SUP-C18 | [] | ["C18"] | JC1 / DZ | ["2CCA2","2CD4F","2CCC1","2CD8F","2CCAA","2CCAD","2CD74","2CEF8","2CEF7"] | SUP-C18/Cimentación de marquesina C18 · capa de limpieza | {"boundingBoxM":{"min":[41.726948,54.363539,-0.5],"max":[43.191899,55.828489,-0.4]},"extentsM":[1.464951,1.46495,0.1],"meshSurfaceM2":3.9,"meshVolumeM3":0.169,"closedSolid":true,"basis":"Magnitudes de las mallas representadas, no cantidades certificadas de obra, compra o fabricación. Las partes pueden compartir superficies; no se suman como un despiece de materiales."} | {"profileId":"concrete_ha20","name":"Hormigón de limpieza HA-20","materialName":"Hormigón de limpieza HA-20","physicalMaterialStatus":"documentado","physicalMaterialSource":"Secciones del fabricante: capa de limpieza de 100 mm; nota 2CED5","appearanceStatus":"criterio_visual","appearanceBasis":"Interpretación visual del material documental; el acabado, tono y parámetros PBR no son una especificación contractual.","note":"La apariencia gráfica no modifica ni confirma la especificación física del material."} | {"elementId":"found_0904_07151943f57280","ifcGuid":"2uvrPOx$PMMx9GNoFYhA_K","ifcClass":"IfcSlab","buildingId":"process_plant","buildingName":"Zona de separación de aire","sourceDocumentId":"LHD2609-JG00100-20260904","sourceRepresentationKind":"foundation"} | {"profileId":"concrete_ha20","name":"Hormigón de limpieza HA-20","status":"criterio_visual","basis":"Interpretación visual del material documental; el acabado, tono y parámetros PBR no son una especificación contractual.","physicalMaterialUnchanged":true} |  | 2CCA2, 2CD4F, 2CCC1, 2CD8F, 2CCAA, 2CCAD, 2CD74, 2CEF8, 2CEF7 | Hormigón de limpieza HA-20 | -1.6 | -1.5 | 1.69 | 0.169 | Contornos y sección documentados por el fabricante | Hormigón de limpieza HA-20 | found_0904_07151943f57280 | documentado | Secciones del fabricante: capa de limpieza de 100 mm; nota 2CED5 | 1.3 | 1.3 | concrete_ha20 | [0.721569,0.709804,0.658824] | 0.98
Cimentación de soporte de tuberías C19 · capa de limpieza | Hormigón de limpieza HA-20 | 1.35226 | 1.35226 | 0.1 | 285 | 285.1 | 3.36 | 0.144 | {"documentId":"LHD2609-JG00100-20260904","title":"Cimentaciones de equipos y pedestales del fabricante · revisión recibida 04/09/2026","date":"2026-09-04","sheet":"ZD1 / DZ-1","fileName":"LHD2609-JG00100_20260904.dwg","revisionCaveat":"Fecha de revisión tomada del nombre recibido; cajetines internos mantienen 02/07/2026 y algunos textos de plantilla.","sourceFileSha256":"b42eb027b7bc0b14c38d1d13514f4899b58a732aa8d0ba2ccf10fa2fc3192890"} | {"name":"Hormigón de limpieza HA-20","status":"documentado","source":"Secciones del fabricante: capa de limpieza de 100 mm; nota 2CED5"} | {"documented":[{"label":"Extensión local X","value":1.2,"unit":"m","source":"2CCA3, 2CD50, 2CCC2, 2CD90, 2CCB2, 2CCB4, 2CD75, 2CEB5, 2CE90","status":"derivada del contorno CAD"},{"label":"Extensión local Y","value":1.2,"unit":"m","source":"2CCA3, 2CD50, 2CCC2, 2CD90, 2CCB2, 2CCB4, 2CD75, 2CEB5, 2CE90","status":"derivada del contorno CAD"},{"label":"Cota inferior relativa adoptada","value":-1.1,"unit":"m","source":"ZD1 / DZ-1","status":"documentada"},{"label":"Cota superior relativa adoptada","value":-1.0,"unit":"m","source":"ZD1 / DZ-1","status":"documentada / separación por material"}],"geometry":[{"label":"Extensión de la malla en X","value":1.3522620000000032,"unit":"m","source":"Geometría releída del IFC; datum absoluto de proceso provisional","status":"derivado"},{"label":"Extensión de la malla en Y","value":1.352261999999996,"unit":"m","source":"Geometría releída del IFC; datum absoluto de proceso provisional","status":"derivado"},{"label":"Extensión de la malla en Z","value":0.1,"unit":"m","source":"Geometría releída del IFC; datum absoluto de proceso provisional","status":"derivado"},{"label":"Cota inferior de visualización","value":285.0,"unit":"m","source":"Geometría releída del IFC; datum absoluto de proceso provisional","status":"derivado"},{"label":"Cota superior de visualización","value":285.1,"unit":"m","source":"Geometría releída del IFC; datum absoluto de proceso provisional","status":"derivado"}]} | [] | {"Cota inferior relativa (m)":-1.1,"Cota superior relativa (m)":-1.0,"Cero absoluto de visualización (m)":286.1,"Estado del cero absoluto":"Provisional","Criterio":"Las cotas relativas proceden del dibujo; la equivalencia absoluta no está confirmada."} | SUP-C19 | [] | ["C19"] | ZD1 / DZ-1 | ["2CCA3","2CD50","2CCC2","2CD90","2CCB2","2CCB4","2CD75","2CEB5","2CE90"] | SUP-C19/Cimentación de soporte de tuberías C19 · capa de limpieza | {"boundingBoxM":{"min":[42.482968,53.818984,0.0],"max":[43.83523,55.171246,0.1]},"extentsM":[1.352262,1.352262,0.1],"meshSurfaceM2":3.36,"meshVolumeM3":0.144,"closedSolid":true,"basis":"Magnitudes de las mallas representadas, no cantidades certificadas de obra, compra o fabricación. Las partes pueden compartir superficies; no se suman como un despiece de materiales."} | {"profileId":"concrete_ha20","name":"Hormigón de limpieza HA-20","materialName":"Hormigón de limpieza HA-20","physicalMaterialStatus":"documentado","physicalMaterialSource":"Secciones del fabricante: capa de limpieza de 100 mm; nota 2CED5","appearanceStatus":"criterio_visual","appearanceBasis":"Interpretación visual del material documental; el acabado, tono y parámetros PBR no son una especificación contractual.","note":"La apariencia gráfica no modifica ni confirma la especificación física del material."} | {"elementId":"found_0904_59ed2d79efb301","ifcGuid":"3c88UOWF9Ilv6i5xWcXZzi","ifcClass":"IfcSlab","buildingId":"process_plant","buildingName":"Zona de separación de aire","sourceDocumentId":"LHD2609-JG00100-20260904","sourceRepresentationKind":"foundation"} | {"profileId":"concrete_ha20","name":"Hormigón de limpieza HA-20","status":"criterio_visual","basis":"Interpretación visual del material documental; el acabado, tono y parámetros PBR no son una especificación contractual.","physicalMaterialUnchanged":true} |  | 2CCA3, 2CD50, 2CCC2, 2CD90, 2CCB2, 2CCB4, 2CD75, 2CEB5, 2CE90 | Hormigón de limpieza HA-20 | -1.1 | -1 | 1.44 | 0.144 | Contornos y sección documentados por el fabricante | Hormigón de limpieza HA-20 | found_0904_59ed2d79efb301 | documentado | Secciones del fabricante: capa de limpieza de 100 mm; nota 2CED5 | 1.2 | 1.2 | concrete_ha20 | [0.721569,0.709804,0.658824] | 0.98
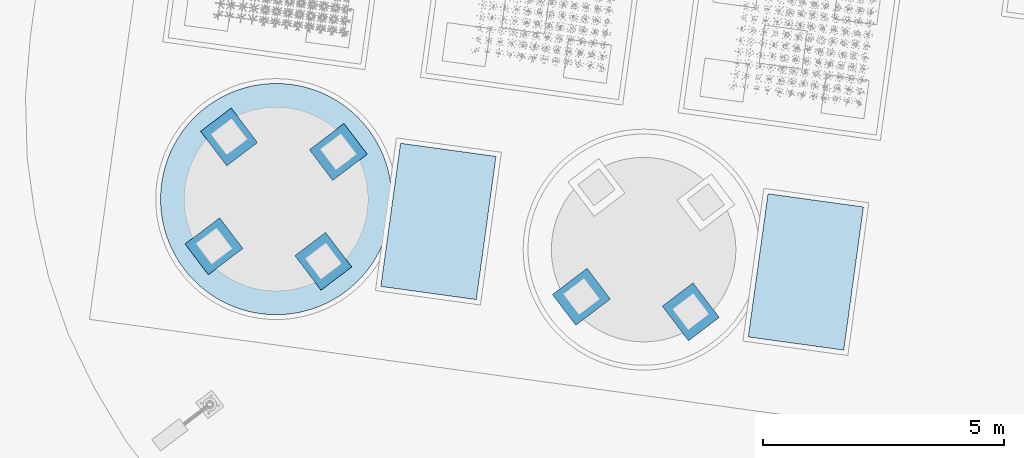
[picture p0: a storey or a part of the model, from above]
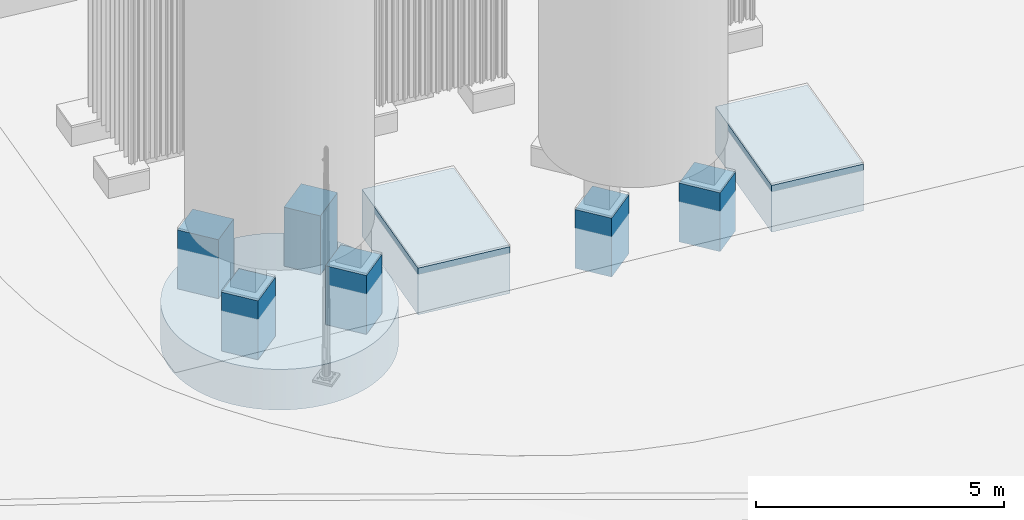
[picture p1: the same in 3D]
Properties of the parts of a building model (IFC4), part 109 of 134

# IfcSlab: Cimentación industrial (108)
Name | Material | Extensión de la malla en X (m) = ExtensionX (m) | Extensión de la malla en Y (m) = ExtensionY (m) | Extensión de la malla en Z (m) = ExtensionZ (m) = Espesor o altura real de sección (m) | Cota inferior de visualización (m) | Cota superior de visualización (m) | SuperficieDeLaMalla (m2) | VolumenGeometrico (m3) | JH_InformacionBIM, source = DocumentoFuente | material | dimensions | issues = IncidenciasPendientes | positioning = PosicionYEstado | assemblyId = Conjunto de cimentación | equipmentIds | supportPositionIds | sectionRef = Sección de referencia | sourceCadHandles | stableElementKey | geometryMetrics | materialAppearance | visualizationIdentity | appearance | Equipos asociados | Identificadores CAD de referencia | JH_Trazabilidad, Material = name | Cota inferior relativa (m) = Cota inferior relativa adoptada (m) | Cota superior relativa (m) = Cota superior relativa adoptada (m) | Área de planta (m²) | Volumen geométrico (m³) | Estado de la geometría | Acabado de visualización = Acabado | Identificador | status | JH_EvidenciaDeMaterial, source | Extensión local X (m) | Extensión local Y (m) | Perfil | ColorRGB | Rugosidad | Incidencias de origen
Cimentación de soporte de tuberías C20 · capa de limpieza | Hormigón de limpieza HA-20 | 1.35226 | 1.35226 | 0.1 | 285 | 285.1 | 3.36 | 0.144 | {"documentId":"LHD2609-JG00100-20260904","title":"Cimentaciones de equipos y pedestales del fabricante · revisión recibida 04/09/2026","date":"2026-09-04","sheet":"ZD1 / DZ-1","fileName":"LHD2609-JG00100_20260904.dwg","revisionCaveat":"Fecha de revisión tomada del nombre recibido; cajetines internos mantienen 02/07/2026 y algunos textos de plantilla.","sourceFileSha256":"b42eb027b7bc0b14c38d1d13514f4899b58a732aa8d0ba2ccf10fa2fc3192890"} | {"name":"Hormigón de limpieza HA-20","status":"documentado","source":"Secciones del fabricante: capa de limpieza de 100 mm; nota 2CED5"} | {"documented":[{"label":"Extensión local X","value":1.2,"unit":"m","source":"2CCA4, 2CD51, 2CCC3, 2CD91, 2CCB3, 2CCB5, 2CD76, 2CEB6, 2CE91","status":"derivada del contorno CAD"},{"label":"Extensión local Y","value":1.2,"unit":"m","source":"2CCA4, 2CD51, 2CCC3, 2CD91, 2CCB3, 2CCB5, 2CD76, 2CEB6, 2CE91","status":"derivada del contorno CAD"},{"label":"Cota inferior relativa adoptada","value":-1.1,"unit":"m","source":"ZD1 / DZ-1","status":"interpretación con conflicto conservado"},{"label":"Cota superior relativa adoptada","value":-1.0,"unit":"m","source":"ZD1 / DZ-1","status":"documentada / separación por material"}],"geometry":[{"label":"Extensión de la malla en X","value":1.3522620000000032,"unit":"m","source":"Geometría releída del IFC; datum absoluto de proceso provisional","status":"derivado"},{"label":"Extensión de la malla en Y","value":1.352261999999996,"unit":"m","source":"Geometría releída del IFC; datum absoluto de proceso provisional","status":"derivado"},{"label":"Extensión de la malla en Z","value":0.1,"unit":"m","source":"Geometría releída del IFC; datum absoluto de proceso provisional","status":"derivado"},{"label":"Cota inferior de visualización","value":285.0,"unit":"m","source":"Geometría releída del IFC; datum absoluto de proceso provisional","status":"derivado"},{"label":"Cota superior de visualización","value":285.1,"unit":"m","source":"Geometría releída del IFC; datum absoluto de proceso provisional","status":"derivado"}]} | ["Identificador original HA-20 en columna de posición; C20 se infiere por secuencia. Se conserva el original y no se interpreta como material."] | {"Cota inferior relativa (m)":-1.1,"Cota superior relativa (m)":-1.0,"Cero absoluto de visualización (m)":286.1,"Estado del cero absoluto":"Provisional","Criterio":"Las cotas relativas proceden del dibujo; la equivalencia absoluta no está confirmada."} | SUP-C20 | [] | ["C20"] | ZD1 / DZ-1 | ["2CCA4","2CD51","2CCC3","2CD91","2CCB3","2CCB5","2CD76","2CEB6","2CE91"] | SUP-C20/Cimentación de soporte de tuberías C20 · capa de limpieza | {"boundingBoxM":{"min":[43.622251,53.66235,0.0],"max":[44.974513,55.014612,0.1]},"extentsM":[1.352262,1.352262,0.1],"meshSurfaceM2":3.36,"meshVolumeM3":0.144,"closedSolid":true,"basis":"Magnitudes de las mallas representadas, no cantidades certificadas de obra, compra o fabricación. Las partes pueden compartir superficies; no se suman como un despiece de materiales."} | {"profileId":"concrete_ha20","name":"Hormigón de limpieza HA-20","materialName":"Hormigón de limpieza HA-20","physicalMaterialStatus":"documentado","physicalMaterialSource":"Secciones del fabricante: capa de limpieza de 100 mm; nota 2CED5","appearanceStatus":"criterio_visual","appearanceBasis":"Interpretación visual del material documental; el acabado, tono y parámetros PBR no son una especificación contractual.","note":"La apariencia gráfica no modifica ni confirma la especificación física del material."} | {"elementId":"found_0904_aa0ff480ffb2e8","ifcGuid":"1Orgv7sdPQzxcoBAANEWG1","ifcClass":"IfcSlab","buildingId":"process_plant","buildingName":"Zona de separación de aire","sourceDocumentId":"LHD2609-JG00100-20260904","sourceRepresentationKind":"foundation"} | {"profileId":"concrete_ha20","name":"Hormigón de limpieza HA-20","status":"criterio_visual","basis":"Interpretación visual del material documental; el acabado, tono y parámetros PBR no son una especificación contractual.","physicalMaterialUnchanged":true} |  | 2CCA4, 2CD51, 2CCC3, 2CD91, 2CCB3, 2CCB5, 2CD76, 2CEB6, 2CE91 | Hormigón de limpieza HA-20 | -1.1 | -1 | 1.44 | 0.144 | Sección y contornos del fabricante; incidencias conservadas | Hormigón de limpieza HA-20 | found_0904_aa0ff480ffb2e8 | documentado | Secciones del fabricante: capa de limpieza de 100 mm; nota 2CED5 | 1.2 | 1.2 | concrete_ha20 | [0.721569,0.709804,0.658824] | 0.98 | Identificador original HA-20 en columna de posición; C20 se infiere por secuencia. Se conserva el original y no se interpreta como material.
Cimentación de soporte de tuberías C21 · capa de limpieza | Hormigón de limpieza HA-20 | 1.35226 | 1.35226 | 0.1 | 285 | 285.1 | 3.36 | 0.144 | {"documentId":"LHD2609-JG00100-20260904","title":"Cimentaciones de equipos y pedestales del fabricante · revisión recibida 04/09/2026","date":"2026-09-04","sheet":"ZD1 / DZ-2","fileName":"LHD2609-JG00100_20260904.dwg","revisionCaveat":"Fecha de revisión tomada del nombre recibido; cajetines internos mantienen 02/07/2026 y algunos textos de plantilla.","sourceFileSha256":"b42eb027b7bc0b14c38d1d13514f4899b58a732aa8d0ba2ccf10fa2fc3192890"} | {"name":"Hormigón de limpieza HA-20","status":"documentado","source":"Secciones del fabricante: capa de limpieza de 100 mm; nota 2CED5"} | {"documented":[{"label":"Extensión local X","value":1.2,"unit":"m","source":"2CCA5, 2CD52, 2CCC4, 2CD92, 2CCBD, 2CCB8, 2CD77, 2CEB7, 2CE92","status":"derivada del contorno CAD"},{"label":"Extensión local Y","value":1.2,"unit":"m","source":"2CCA5, 2CD52, 2CCC4, 2CD92, 2CCBD, 2CCB8, 2CD77, 2CEB7, 2CE92","status":"derivada del contorno CAD"},{"label":"Cota inferior relativa adoptada","value":-1.1,"unit":"m","source":"ZD1 / DZ-2","status":"documentada"},{"label":"Cota superior relativa adoptada","value":-1.0,"unit":"m","source":"ZD1 / DZ-2","status":"documentada / separación por material"}],"geometry":[{"label":"Extensión de la malla en X","value":1.3522609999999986,"unit":"m","source":"Geometría releída del IFC; datum absoluto de proceso provisional","status":"derivado"},{"label":"Extensión de la malla en Y","value":1.3522609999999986,"unit":"m","source":"Geometría releída del IFC; datum absoluto de proceso provisional","status":"derivado"},{"label":"Extensión de la malla en Z","value":0.1,"unit":"m","source":"Geometría releída del IFC; datum absoluto de proceso provisional","status":"derivado"},{"label":"Cota inferior de visualización","value":285.0,"unit":"m","source":"Geometría releída del IFC; datum absoluto de proceso provisional","status":"derivado"},{"label":"Cota superior de visualización","value":285.1,"unit":"m","source":"Geometría releída del IFC; datum absoluto de proceso provisional","status":"derivado"}]} | [] | {"Cota inferior relativa (m)":-1.1,"Cota superior relativa (m)":-1.0,"Cero absoluto de visualización (m)":286.1,"Estado del cero absoluto":"Provisional","Criterio":"Las cotas relativas proceden del dibujo; la equivalencia absoluta no está confirmada."} | SUP-C21 | [] | ["C21"] | ZD1 / DZ-2 | ["2CCA5","2CD52","2CCC4","2CD92","2CCBD","2CCB8","2CD77","2CEB7","2CE92"] | SUP-C21/Cimentación de soporte de tuberías C21 · capa de limpieza | {"boundingBoxM":{"min":[51.285156,53.41634,0.0],"max":[52.637417,54.768601,0.1]},"extentsM":[1.352261,1.352261,0.1],"meshSurfaceM2":3.36,"meshVolumeM3":0.144,"closedSolid":true,"basis":"Magnitudes de las mallas representadas, no cantidades certificadas de obra, compra o fabricación. Las partes pueden compartir superficies; no se suman como un despiece de materiales."} | {"profileId":"concrete_ha20","name":"Hormigón de limpieza HA-20","materialName":"Hormigón de limpieza HA-20","physicalMaterialStatus":"documentado","physicalMaterialSource":"Secciones del fabricante: capa de limpieza de 100 mm; nota 2CED5","appearanceStatus":"criterio_visual","appearanceBasis":"Interpretación visual del material documental; el acabado, tono y parámetros PBR no son una especificación contractual.","note":"La apariencia gráfica no modifica ni confirma la especificación física del material."} | {"elementId":"found_0904_e2bbdc21f0b06b","ifcGuid":"04VwAMrXnO0BoN4keub_aw","ifcClass":"IfcSlab","buildingId":"process_plant","buildingName":"Zona de separación de aire","sourceDocumentId":"LHD2609-JG00100-20260904","sourceRepresentationKind":"foundation"} | {"profileId":"concrete_ha20","name":"Hormigón de limpieza HA-20","status":"criterio_visual","basis":"Interpretación visual del material documental; el acabado, tono y parámetros PBR no son una especificación contractual.","physicalMaterialUnchanged":true} |  | 2CCA5, 2CD52, 2CCC4, 2CD92, 2CCBD, 2CCB8, 2CD77, 2CEB7, 2CE92 | Hormigón de limpieza HA-20 | -1.1 | -1 | 1.44 | 0.144 | Contornos y sección documentados por el fabricante | Hormigón de limpieza HA-20 | found_0904_e2bbdc21f0b06b | documentado | Secciones del fabricante: capa de limpieza de 100 mm; nota 2CED5 | 1.2 | 1.2 | concrete_ha20 | [0.721569,0.709804,0.658824] | 0.98
Cimentación de soporte de tuberías C22 · capa de limpieza | Hormigón de limpieza HA-20 | 1.35226 | 1.35226 | 0.1 | 285 | 285.1 | 3.36 | 0.144 | {"documentId":"LHD2609-JG00100-20260904","title":"Cimentaciones de equipos y pedestales del fabricante · revisión recibida 04/09/2026","date":"2026-09-04","sheet":"ZD1 / DZ-2","fileName":"LHD2609-JG00100_20260904.dwg","revisionCaveat":"Fecha de revisión tomada del nombre recibido; cajetines internos mantienen 02/07/2026 y algunos textos de plantilla.","sourceFileSha256":"b42eb027b7bc0b14c38d1d13514f4899b58a732aa8d0ba2ccf10fa2fc3192890"} | {"name":"Hormigón de limpieza HA-20","status":"documentado","source":"Secciones del fabricante: capa de limpieza de 100 mm; nota 2CED5"} | {"documented":[{"label":"Extensión local X","value":1.2,"unit":"m","source":"2CCA6, 2CD53, 2CCC5, 2CD93, 2CCBB, 2CCBC, 2CD82, 2CEB8, 2CE93","status":"derivada del contorno CAD"},{"label":"Extensión local Y","value":1.2,"unit":"m","source":"2CCA6, 2CD53, 2CCC5, 2CD93, 2CCBB, 2CCBC, 2CD82, 2CEB8, 2CE93","status":"derivada del contorno CAD"},{"label":"Cota inferior relativa adoptada","value":-1.1,"unit":"m","source":"ZD1 / DZ-2","status":"documentada"},{"label":"Cota superior relativa adoptada","value":-1.0,"unit":"m","source":"ZD1 / DZ-2","status":"documentada / separación por material"}],"geometry":[{"label":"Extensión de la malla en X","value":1.352261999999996,"unit":"m","source":"Geometría releída del IFC; datum absoluto de proceso provisional","status":"derivado"},{"label":"Extensión de la malla en Y","value":1.352261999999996,"unit":"m","source":"Geometría releída del IFC; datum absoluto de proceso provisional","status":"derivado"},{"label":"Extensión de la malla en Z","value":0.1,"unit":"m","source":"Geometría releída del IFC; datum absoluto de proceso provisional","status":"derivado"},{"label":"Cota inferior de visualización","value":285.0,"unit":"m","source":"Geometría releída del IFC; datum absoluto de proceso provisional","status":"derivado"},{"label":"Cota superior de visualización","value":285.1,"unit":"m","source":"Geometría releída del IFC; datum absoluto de proceso provisional","status":"derivado"}]} | [] | {"Cota inferior relativa (m)":-1.1,"Cota superior relativa (m)":-1.0,"Cero absoluto de visualización (m)":286.1,"Estado del cero absoluto":"Provisional","Criterio":"Las cotas relativas proceden del dibujo; la equivalencia absoluta no está confirmada."} | SUP-C22 | [] | ["C22"] | ZD1 / DZ-2 | ["2CCA6","2CD53","2CCC5","2CD93","2CCBB","2CCBC","2CD82","2CEB8","2CE93"] | SUP-C22/Cimentación de soporte de tuberías C22 · capa de limpieza | {"boundingBoxM":{"min":[53.91046,53.055399,0.0],"max":[55.262722,54.407661,0.1]},"extentsM":[1.352262,1.352262,0.1],"meshSurfaceM2":3.36,"meshVolumeM3":0.144,"closedSolid":true,"basis":"Magnitudes de las mallas representadas, no cantidades certificadas de obra, compra o fabricación. Las partes pueden compartir superficies; no se suman como un despiece de materiales."} | {"profileId":"concrete_ha20","name":"Hormigón de limpieza HA-20","materialName":"Hormigón de limpieza HA-20","physicalMaterialStatus":"documentado","physicalMaterialSource":"Secciones del fabricante: capa de limpieza de 100 mm; nota 2CED5","appearanceStatus":"criterio_visual","appearanceBasis":"Interpretación visual del material documental; el acabado, tono y parámetros PBR no son una especificación contractual.","note":"La apariencia gráfica no modifica ni confirma la especificación física del material."} | {"elementId":"found_0904_62582f5ceacb96","ifcGuid":"31qHtM5D9MFxrqCsb$S68k","ifcClass":"IfcSlab","buildingId":"process_plant","buildingName":"Zona de separación de aire","sourceDocumentId":"LHD2609-JG00100-20260904","sourceRepresentationKind":"foundation"} | {"profileId":"concrete_ha20","name":"Hormigón de limpieza HA-20","status":"criterio_visual","basis":"Interpretación visual del material documental; el acabado, tono y parámetros PBR no son una especificación contractual.","physicalMaterialUnchanged":true} |  | 2CCA6, 2CD53, 2CCC5, 2CD93, 2CCBB, 2CCBC, 2CD82, 2CEB8, 2CE93 | Hormigón de limpieza HA-20 | -1.1 | -1 | 1.44 | 0.144 | Contornos y sección documentados por el fabricante | Hormigón de limpieza HA-20 | found_0904_62582f5ceacb96 | documentado | Secciones del fabricante: capa de limpieza de 100 mm; nota 2CED5 | 1.2 | 1.2 | concrete_ha20 | [0.721569,0.709804,0.658824] | 0.98
Cimentación de soporte de tuberías C23 · capa de limpieza | Hormigón de limpieza HA-20 | 1.35226 | 1.35226 | 0.1 | 285 | 285.1 | 3.36 | 0.144 | {"documentId":"LHD2609-JG00100-20260904","title":"Cimentaciones de equipos y pedestales del fabricante · revisión recibida 04/09/2026","date":"2026-09-04","sheet":"ZD1 / DZ-2","fileName":"LHD2609-JG00100_20260904.dwg","revisionCaveat":"Fecha de revisión tomada del nombre recibido; cajetines internos mantienen 02/07/2026 y algunos textos de plantilla.","sourceFileSha256":"b42eb027b7bc0b14c38d1d13514f4899b58a732aa8d0ba2ccf10fa2fc3192890"} | {"name":"Hormigón de limpieza HA-20","status":"documentado","source":"Secciones del fabricante: capa de limpieza de 100 mm; nota 2CED5"} | {"documented":[{"label":"Extensión local X","value":1.2,"unit":"m","source":"2CCA7, 2CD5F, 2CCC6, 2CD94, 2CCB9, 2CCBA, 2CD83, 2CEB9, 2CE94","status":"derivada del contorno CAD"},{"label":"Extensión local Y","value":1.2,"unit":"m","source":"2CCA7, 2CD5F, 2CCC6, 2CD94, 2CCB9, 2CCBA, 2CD83, 2CEB9, 2CE94","status":"derivada del contorno CAD"},{"label":"Cota inferior relativa adoptada","value":-1.1,"unit":"m","source":"ZD1 / DZ-2","status":"documentada"},{"label":"Cota superior relativa adoptada","value":-1.0,"unit":"m","source":"ZD1 / DZ-2","status":"documentada / separación por material"}],"geometry":[{"label":"Extensión de la malla en X","value":1.3522620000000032,"unit":"m","source":"Geometría releída del IFC; datum absoluto de proceso provisional","status":"derivado"},{"label":"Extensión de la malla en Y","value":1.3522620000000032,"unit":"m","source":"Geometría releída del IFC; datum absoluto de proceso provisional","status":"derivado"},{"label":"Extensión de la malla en Z","value":0.1,"unit":"m","source":"Geometría releída del IFC; datum absoluto de proceso provisional","status":"derivado"},{"label":"Cota inferior de visualización","value":285.0,"unit":"m","source":"Geometría releída del IFC; datum absoluto de proceso provisional","status":"derivado"},{"label":"Cota superior de visualización","value":285.1,"unit":"m","source":"Geometría releída del IFC; datum absoluto de proceso provisional","status":"derivado"}]} | [] | {"Cota inferior relativa (m)":-1.1,"Cota superior relativa (m)":-1.0,"Cero absoluto de visualización (m)":286.1,"Estado del cero absoluto":"Provisional","Criterio":"Las cotas relativas proceden del dibujo; la equivalencia absoluta no está confirmada."} | SUP-C23 | [] | ["C23"] | ZD1 / DZ-2 | ["2CCA7","2CD5F","2CCC6","2CD94","2CCB9","2CCBA","2CD83","2CEB9","2CE94"] | SUP-C23/Cimentación de soporte de tuberías C23 · capa de limpieza | {"boundingBoxM":{"min":[56.219992,52.233169,0.0],"max":[57.572254,53.585431,0.1]},"extentsM":[1.352262,1.352262,0.1],"meshSurfaceM2":3.36,"meshVolumeM3":0.144,"closedSolid":true,"basis":"Magnitudes de las mallas representadas, no cantidades certificadas de obra, compra o fabricación. Las partes pueden compartir superficies; no se suman como un despiece de materiales."} | {"profileId":"concrete_ha20","name":"Hormigón de limpieza HA-20","materialName":"Hormigón de limpieza HA-20","physicalMaterialStatus":"documentado","physicalMaterialSource":"Secciones del fabricante: capa de limpieza de 100 mm; nota 2CED5","appearanceStatus":"criterio_visual","appearanceBasis":"Interpretación visual del material documental; el acabado, tono y parámetros PBR no son una especificación contractual.","note":"La apariencia gráfica no modifica ni confirma la especificación física del material."} | {"elementId":"found_0904_0148cba0bcec71","ifcGuid":"0AW5cu3WXLaQpE7FIYGDSl","ifcClass":"IfcSlab","buildingId":"process_plant","buildingName":"Zona de separación de aire","sourceDocumentId":"LHD2609-JG00100-20260904","sourceRepresentationKind":"foundation"} | {"profileId":"concrete_ha20","name":"Hormigón de limpieza HA-20","status":"criterio_visual","basis":"Interpretación visual del material documental; el acabado, tono y parámetros PBR no son una especificación contractual.","physicalMaterialUnchanged":true} |  | 2CCA7, 2CD5F, 2CCC6, 2CD94, 2CCB9, 2CCBA, 2CD83, 2CEB9, 2CE94 | Hormigón de limpieza HA-20 | -1.1 | -1 | 1.44 | 0.144 | Contornos y sección documentados por el fabricante | Hormigón de limpieza HA-20 | found_0904_0148cba0bcec71 | documentado | Secciones del fabricante: capa de limpieza de 100 mm; nota 2CED5 | 1.2 | 1.2 | concrete_ha20 | [0.721569,0.709804,0.658824] | 0.98
Cimentación de soporte de tuberías C24 · capa de limpieza | Hormigón de limpieza HA-20 | 1.35226 | 1.35226 | 0.1 | 285 | 285.1 | 3.36 | 0.144 | {"documentId":"LHD2609-JG00100-20260904","title":"Cimentaciones de equipos y pedestales del fabricante · revisión recibida 04/09/2026","date":"2026-09-04","sheet":"ZD1 / DZ-2","fileName":"LHD2609-JG00100_20260904.dwg","revisionCaveat":"Fecha de revisión tomada del nombre recibido; cajetines internos mantienen 02/07/2026 y algunos textos de plantilla.","sourceFileSha256":"b42eb027b7bc0b14c38d1d13514f4899b58a732aa8d0ba2ccf10fa2fc3192890"} | {"name":"Hormigón de limpieza HA-20","status":"documentado","source":"Secciones del fabricante: capa de limpieza de 100 mm; nota 2CED5"} | {"documented":[{"label":"Extensión local X","value":1.2,"unit":"m","source":"2CCA8, 2CD60, 2CCC7, 2CD95, 2CCB6, 2CCB7, 2CD84, 2CEBA, 2CE95","status":"derivada del contorno CAD"},{"label":"Extensión local Y","value":1.2,"unit":"m","source":"2CCA8, 2CD60, 2CCC7, 2CD95, 2CCB6, 2CCB7, 2CD84, 2CEBA, 2CE95","status":"derivada del contorno CAD"},{"label":"Cota inferior relativa adoptada","value":-1.1,"unit":"m","source":"ZD1 / DZ-2","status":"documentada"},{"label":"Cota superior relativa adoptada","value":-1.0,"unit":"m","source":"ZD1 / DZ-2","status":"documentada / separación por material"}],"geometry":[{"label":"Extensión de la malla en X","value":1.352261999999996,"unit":"m","source":"Geometría releída del IFC; datum absoluto de proceso provisional","status":"derivado"},{"label":"Extensión de la malla en Y","value":1.352261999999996,"unit":"m","source":"Geometría releída del IFC; datum absoluto de proceso provisional","status":"derivado"},{"label":"Extensión de la malla en Z","value":0.1,"unit":"m","source":"Geometría releída del IFC; datum absoluto de proceso provisional","status":"derivado"},{"label":"Cota inferior de visualización","value":285.0,"unit":"m","source":"Geometría releída del IFC; datum absoluto de proceso provisional","status":"derivado"},{"label":"Cota superior de visualización","value":285.1,"unit":"m","source":"Geometría releída del IFC; datum absoluto de proceso provisional","status":"derivado"}]} | [] | {"Cota inferior relativa (m)":-1.1,"Cota superior relativa (m)":-1.0,"Cero absoluto de visualización (m)":286.1,"Estado del cero absoluto":"Provisional","Criterio":"Las cotas relativas proceden del dibujo; la equivalencia absoluta no está confirmada."} | SUP-C24 | [] | ["C24"] | ZD1 / DZ-2 | ["2CCA8","2CD60","2CCC7","2CD95","2CCB6","2CCB7","2CD84","2CEBA","2CE95"] | SUP-C24/Cimentación de soporte de tuberías C24 · capa de limpieza | {"boundingBoxM":{"min":[56.015686,50.747148,0.0],"max":[57.367948,52.09941,0.1]},"extentsM":[1.352262,1.352262,0.1],"meshSurfaceM2":3.36,"meshVolumeM3":0.144,"closedSolid":true,"basis":"Magnitudes de las mallas representadas, no cantidades certificadas de obra, compra o fabricación. Las partes pueden compartir superficies; no se suman como un despiece de materiales."} | {"profileId":"concrete_ha20","name":"Hormigón de limpieza HA-20","materialName":"Hormigón de limpieza HA-20","physicalMaterialStatus":"documentado","physicalMaterialSource":"Secciones del fabricante: capa de limpieza de 100 mm; nota 2CED5","appearanceStatus":"criterio_visual","appearanceBasis":"Interpretación visual del material documental; el acabado, tono y parámetros PBR no son una especificación contractual.","note":"La apariencia gráfica no modifica ni confirma la especificación física del material."} | {"elementId":"found_0904_cf8f73b10bb1e1","ifcGuid":"1NCeWlaqHGzfxDK$uuNkZo","ifcClass":"IfcSlab","buildingId":"process_plant","buildingName":"Zona de separación de aire","sourceDocumentId":"LHD2609-JG00100-20260904","sourceRepresentationKind":"foundation"} | {"profileId":"concrete_ha20","name":"Hormigón de limpieza HA-20","status":"criterio_visual","basis":"Interpretación visual del material documental; el acabado, tono y parámetros PBR no son una especificación contractual.","physicalMaterialUnchanged":true} |  | 2CCA8, 2CD60, 2CCC7, 2CD95, 2CCB6, 2CCB7, 2CD84, 2CEBA, 2CE95 | Hormigón de limpieza HA-20 | -1.1 | -1 | 1.44 | 0.144 | Contornos y sección documentados por el fabricante | Hormigón de limpieza HA-20 | found_0904_cf8f73b10bb1e1 | documentado | Secciones del fabricante: capa de limpieza de 100 mm; nota 2CED5 | 1.2 | 1.2 | concrete_ha20 | [0.721569,0.709804,0.658824] | 0.98
Cimentación de soporte de tuberías C25 · capa de limpieza | Hormigón de limpieza HA-20 | 1.35226 | 1.35226 | 0.1 | 285 | 285.1 | 3.36 | 0.144 | {"documentId":"LHD2609-JG00100-20260904","title":"Cimentaciones de equipos y pedestales del fabricante · revisión recibida 04/09/2026","date":"2026-09-04","sheet":"ZD1 / DZ-1","fileName":"LHD2609-JG00100_20260904.dwg","revisionCaveat":"Fecha de revisión tomada del nombre recibido; cajetines internos mantienen 02/07/2026 y algunos textos de plantilla.","sourceFileSha256":"b42eb027b7bc0b14c38d1d13514f4899b58a732aa8d0ba2ccf10fa2fc3192890"} | {"name":"Hormigón de limpieza HA-20","status":"documentado","source":"Secciones del fabricante: capa de limpieza de 100 mm; nota 2CED5"} | {"documented":[{"label":"Extensión local X","value":1.2,"unit":"m","source":"2CCDA, 2CD54, 2CCF2, 2CD96, 2CCE3, 2CCE4, 2CD78, 2CEBB, 2CE96","status":"derivada del contorno CAD"},{"label":"Extensión local Y","value":1.2,"unit":"m","source":"2CCDA, 2CD54, 2CCF2, 2CD96, 2CCE3, 2CCE4, 2CD78, 2CEBB, 2CE96","status":"derivada del contorno CAD"},{"label":"Cota inferior relativa adoptada","value":-1.1,"unit":"m","source":"ZD1 / DZ-1","status":"documentada"},{"label":"Cota superior relativa adoptada","value":-1.0,"unit":"m","source":"ZD1 / DZ-1","status":"documentada / separación por material"}],"geometry":[{"label":"Extensión de la malla en X","value":1.3522620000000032,"unit":"m","source":"Geometría releída del IFC; datum absoluto de proceso provisional","status":"derivado"},{"label":"Extensión de la malla en Y","value":1.3522620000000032,"unit":"m","source":"Geometría releída del IFC; datum absoluto de proceso provisional","status":"derivado"},{"label":"Extensión de la malla en Z","value":0.1,"unit":"m","source":"Geometría releída del IFC; datum absoluto de proceso provisional","status":"derivado"},{"label":"Cota inferior de visualización","value":285.0,"unit":"m","source":"Geometría releída del IFC; datum absoluto de proceso provisional","status":"derivado"},{"label":"Cota superior de visualización","value":285.1,"unit":"m","source":"Geometría releída del IFC; datum absoluto de proceso provisional","status":"derivado"}]} | [] | {"Cota inferior relativa (m)":-1.1,"Cota superior relativa (m)":-1.0,"Cero absoluto de visualización (m)":286.1,"Estado del cero absoluto":"Provisional","Criterio":"Las cotas relativas proceden del dibujo; la equivalencia absoluta no está confirmada."} | SUP-C25 | [] | ["C25"] | ZD1 / DZ-1 | ["2CCDA","2CD54","2CCF2","2CD96","2CCE3","2CCE4","2CD78","2CEBB","2CE96"] | SUP-C25/Cimentación de soporte de tuberías C25 · capa de limpieza | {"boundingBoxM":{"min":[60.069095,51.77968,0.0],"max":[61.421357,53.131942,0.1]},"extentsM":[1.352262,1.352262,0.1],"meshSurfaceM2":3.36,"meshVolumeM3":0.144,"closedSolid":true,"basis":"Magnitudes de las mallas representadas, no cantidades certificadas de obra, compra o fabricación. Las partes pueden compartir superficies; no se suman como un despiece de materiales."} | {"profileId":"concrete_ha20","name":"Hormigón de limpieza HA-20","materialName":"Hormigón de limpieza HA-20","physicalMaterialStatus":"documentado","physicalMaterialSource":"Secciones del fabricante: capa de limpieza de 100 mm; nota 2CED5","appearanceStatus":"criterio_visual","appearanceBasis":"Interpretación visual del material documental; el acabado, tono y parámetros PBR no son una especificación contractual.","note":"La apariencia gráfica no modifica ni confirma la especificación física del material."} | {"elementId":"found_0904_89c243ad380229","ifcGuid":"0Bsxees21OKepeb8hAOF_5","ifcClass":"IfcSlab","buildingId":"process_plant","buildingName":"Zona de separación de aire","sourceDocumentId":"LHD2609-JG00100-20260904","sourceRepresentationKind":"foundation"} | {"profileId":"concrete_ha20","name":"Hormigón de limpieza HA-20","status":"criterio_visual","basis":"Interpretación visual del material documental; el acabado, tono y parámetros PBR no son una especificación contractual.","physicalMaterialUnchanged":true} |  | 2CCDA, 2CD54, 2CCF2, 2CD96, 2CCE3, 2CCE4, 2CD78, 2CEBB, 2CE96 | Hormigón de limpieza HA-20 | -1.1 | -1 | 1.44 | 0.144 | Contornos y sección documentados por el fabricante | Hormigón de limpieza HA-20 | found_0904_89c243ad380229 | documentado | Secciones del fabricante: capa de limpieza de 100 mm; nota 2CED5 | 1.2 | 1.2 | concrete_ha20 | [0.721569,0.709804,0.658824] | 0.98
Cimentación de soporte de tuberías C26 · capa de limpieza | Hormigón de limpieza HA-20 | 1.35226 | 1.35226 | 0.1 | 285 | 285.1 | 3.36 | 0.144 | {"documentId":"LHD2609-JG00100-20260904","title":"Cimentaciones de equipos y pedestales del fabricante · revisión recibida 04/09/2026","date":"2026-09-04","sheet":"ZD1 / DZ-1","fileName":"LHD2609-JG00100_20260904.dwg","revisionCaveat":"Fecha de revisión tomada del nombre recibido; cajetines internos mantienen 02/07/2026 y algunos textos de plantilla.","sourceFileSha256":"b42eb027b7bc0b14c38d1d13514f4899b58a732aa8d0ba2ccf10fa2fc3192890"} | {"name":"Hormigón de limpieza HA-20","status":"documentado","source":"Secciones del fabricante: capa de limpieza de 100 mm; nota 2CED5"} | {"documented":[{"label":"Extensión local X","value":1.2,"unit":"m","source":"2CCDB, 2CD55, 2CCF3, 2CD97, 2CCE2, 2CCE5, 2CD79, 2CEBC, 2CE97","status":"derivada del contorno CAD"},{"label":"Extensión local Y","value":1.2,"unit":"m","source":"2CCDB, 2CD55, 2CCF3, 2CD97, 2CCE2, 2CCE5, 2CD79, 2CEBC, 2CE97","status":"derivada del contorno CAD"},{"label":"Cota inferior relativa adoptada","value":-1.1,"unit":"m","source":"ZD1 / DZ-1","status":"documentada"},{"label":"Cota superior relativa adoptada","value":-1.0,"unit":"m","source":"ZD1 / DZ-1","status":"documentada / separación por material"}],"geometry":[{"label":"Extensión de la malla en X","value":1.3522609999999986,"unit":"m","source":"Geometría releída del IFC; datum absoluto de proceso provisional","status":"derivado"},{"label":"Extensión de la malla en Y","value":1.3522620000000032,"unit":"m","source":"Geometría releída del IFC; datum absoluto de proceso provisional","status":"derivado"},{"label":"Extensión de la malla en Z","value":0.1,"unit":"m","source":"Geometría releída del IFC; datum absoluto de proceso provisional","status":"derivado"},{"label":"Cota inferior de visualización","value":285.0,"unit":"m","source":"Geometría releída del IFC; datum absoluto de proceso provisional","status":"derivado"},{"label":"Cota superior de visualización","value":285.1,"unit":"m","source":"Geometría releída del IFC; datum absoluto de proceso provisional","status":"derivado"}]} | [] | {"Cota inferior relativa (m)":-1.1,"Cota superior relativa (m)":-1.0,"Cero absoluto de visualización (m)":286.1,"Estado del cero absoluto":"Provisional","Criterio":"Las cotas relativas proceden del dibujo; la equivalencia absoluta no está confirmada."} | SUP-C26 | [] | ["C26"] | ZD1 / DZ-1 | ["2CCDB","2CD55","2CCF3","2CD97","2CCE2","2CCE5","2CD79","2CEBC","2CE97"] | SUP-C26/Cimentación de soporte de tuberías C26 · capa de limpieza | {"boundingBoxM":{"min":[61.802787,51.541323,0.0],"max":[63.155048,52.893585,0.1]},"extentsM":[1.352261,1.352262,0.1],"meshSurfaceM2":3.359999,"meshVolumeM3":0.144,"closedSolid":true,"basis":"Magnitudes de las mallas representadas, no cantidades certificadas de obra, compra o fabricación. Las partes pueden compartir superficies; no se suman como un despiece de materiales."} | {"profileId":"concrete_ha20","name":"Hormigón de limpieza HA-20","materialName":"Hormigón de limpieza HA-20","physicalMaterialStatus":"documentado","physicalMaterialSource":"Secciones del fabricante: capa de limpieza de 100 mm; nota 2CED5","appearanceStatus":"criterio_visual","appearanceBasis":"Interpretación visual del material documental; el acabado, tono y parámetros PBR no son una especificación contractual.","note":"La apariencia gráfica no modifica ni confirma la especificación física del material."} | {"elementId":"found_0904_4243d79250e3ac","ifcGuid":"2mO27KCAHIkeJ00tKQ7PQ8","ifcClass":"IfcSlab","buildingId":"process_plant","buildingName":"Zona de separación de aire","sourceDocumentId":"LHD2609-JG00100-20260904","sourceRepresentationKind":"foundation"} | {"profileId":"concrete_ha20","name":"Hormigón de limpieza HA-20","status":"criterio_visual","basis":"Interpretación visual del material documental; el acabado, tono y parámetros PBR no son una especificación contractual.","physicalMaterialUnchanged":true} |  | 2CCDB, 2CD55, 2CCF3, 2CD97, 2CCE2, 2CCE5, 2CD79, 2CEBC, 2CE97 | Hormigón de limpieza HA-20 | -1.1 | -1 | 1.44 | 0.144 | Contornos y sección documentados por el fabricante | Hormigón de limpieza HA-20 | found_0904_4243d79250e3ac | documentado | Secciones del fabricante: capa de limpieza de 100 mm; nota 2CED5 | 1.2 | 1.2 | concrete_ha20 | [0.721569,0.709804,0.658824] | 0.98
Cimentación de soporte de tuberías C27 · capa de limpieza | Hormigón de limpieza HA-20 | 1.35226 | 1.35226 | 0.1 | 285 | 285.1 | 3.36 | 0.144 | {"documentId":"LHD2609-JG00100-20260904","title":"Cimentaciones de equipos y pedestales del fabricante · revisión recibida 04/09/2026","date":"2026-09-04","sheet":"ZD1 / DZ-1","fileName":"LHD2609-JG00100_20260904.dwg","revisionCaveat":"Fecha de revisión tomada del nombre recibido; cajetines internos mantienen 02/07/2026 y algunos textos de plantilla.","sourceFileSha256":"b42eb027b7bc0b14c38d1d13514f4899b58a732aa8d0ba2ccf10fa2fc3192890"} | {"name":"Hormigón de limpieza HA-20","status":"documentado","source":"Secciones del fabricante: capa de limpieza de 100 mm; nota 2CED5"} | {"documented":[{"label":"Extensión local X","value":1.2,"unit":"m","source":"2CCDC, 2CD56, 2CCF4, 2CD98, 2CCE6, 2CCE8, 2CD7A, 2CEBD, 2CE98","status":"derivada del contorno CAD"},{"label":"Extensión local Y","value":1.2,"unit":"m","source":"2CCDC, 2CD56, 2CCF4, 2CD98, 2CCE6, 2CCE8, 2CD7A, 2CEBD, 2CE98","status":"derivada del contorno CAD"},{"label":"Cota inferior relativa adoptada","value":-1.1,"unit":"m","source":"ZD1 / DZ-1","status":"documentada"},{"label":"Cota superior relativa adoptada","value":-1.0,"unit":"m","source":"ZD1 / DZ-1","status":"documentada / separación por material"}],"geometry":[{"label":"Extensión de la malla en X","value":1.3522620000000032,"unit":"m","source":"Geometría releída del IFC; datum absoluto de proceso provisional","status":"derivado"},{"label":"Extensión de la malla en Y","value":1.3522620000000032,"unit":"m","source":"Geometría releída del IFC; datum absoluto de proceso provisional","status":"derivado"},{"label":"Extensión de la malla en Z","value":0.1,"unit":"m","source":"Geometría releída del IFC; datum absoluto de proceso provisional","status":"derivado"},{"label":"Cota inferior de visualización","value":285.0,"unit":"m","source":"Geometría releída del IFC; datum absoluto de proceso provisional","status":"derivado"},{"label":"Cota superior de visualización","value":285.1,"unit":"m","source":"Geometría releída del IFC; datum absoluto de proceso provisional","status":"derivado"}]} | [] | {"Cota inferior relativa (m)":-1.1,"Cota superior relativa (m)":-1.0,"Cero absoluto de visualización (m)":286.1,"Estado del cero absoluto":"Provisional","Criterio":"Las cotas relativas proceden del dibujo; la equivalencia absoluta no está confirmada."} | SUP-C27 | [] | ["C27"] | ZD1 / DZ-1 | ["2CCDC","2CD56","2CCF4","2CD98","2CCE6","2CCE8","2CD7A","2CEBD","2CE98"] | SUP-C27/Cimentación de soporte de tuberías C27 · capa de limpieza | {"boundingBoxM":{"min":[59.830738,50.045989,0.0],"max":[61.183,51.398251,0.1]},"extentsM":[1.352262,1.352262,0.1],"meshSurfaceM2":3.36,"meshVolumeM3":0.144,"closedSolid":true,"basis":"Magnitudes de las mallas representadas, no cantidades certificadas de obra, compra o fabricación. Las partes pueden compartir superficies; no se suman como un despiece de materiales."} | {"profileId":"concrete_ha20","name":"Hormigón de limpieza HA-20","materialName":"Hormigón de limpieza HA-20","physicalMaterialStatus":"documentado","physicalMaterialSource":"Secciones del fabricante: capa de limpieza de 100 mm; nota 2CED5","appearanceStatus":"criterio_visual","appearanceBasis":"Interpretación visual del material documental; el acabado, tono y parámetros PBR no son una especificación contractual.","note":"La apariencia gráfica no modifica ni confirma la especificación física del material."} | {"elementId":"found_0904_f5af5caa0a18e3","ifcGuid":"0wHo23dC1I1RR6ru_alKfo","ifcClass":"IfcSlab","buildingId":"process_plant","buildingName":"Zona de separación de aire","sourceDocumentId":"LHD2609-JG00100-20260904","sourceRepresentationKind":"foundation"} | {"profileId":"concrete_ha20","name":"Hormigón de limpieza HA-20","status":"criterio_visual","basis":"Interpretación visual del material documental; el acabado, tono y parámetros PBR no son una especificación contractual.","physicalMaterialUnchanged":true} |  | 2CCDC, 2CD56, 2CCF4, 2CD98, 2CCE6, 2CCE8, 2CD7A, 2CEBD, 2CE98 | Hormigón de limpieza HA-20 | -1.1 | -1 | 1.44 | 0.144 | Contornos y sección documentados por el fabricante | Hormigón de limpieza HA-20 | found_0904_f5af5caa0a18e3 | documentado | Secciones del fabricante: capa de limpieza de 100 mm; nota 2CED5 | 1.2 | 1.2 | concrete_ha20 | [0.721569,0.709804,0.658824] | 0.98
Cimentación de soporte de tuberías C28 · capa de limpieza | Hormigón de limpieza HA-20 | 1.35226 | 1.35226 | 0.1 | 285 | 285.1 | 3.36 | 0.144 | {"documentId":"LHD2609-JG00100-20260904","title":"Cimentaciones de equipos y pedestales del fabricante · revisión recibida 04/09/2026","date":"2026-09-04","sheet":"ZD1 / DZ-1","fileName":"LHD2609-JG00100_20260904.dwg","revisionCaveat":"Fecha de revisión tomada del nombre recibido; cajetines internos mantienen 02/07/2026 y algunos textos de plantilla.","sourceFileSha256":"b42eb027b7bc0b14c38d1d13514f4899b58a732aa8d0ba2ccf10fa2fc3192890"} | {"name":"Hormigón de limpieza HA-20","status":"documentado","source":"Secciones del fabricante: capa de limpieza de 100 mm; nota 2CED5"} | {"documented":[{"label":"Extensión local X","value":1.2,"unit":"m","source":"2CCDD, 2CD57, 2CCF5, 2CD99, 2CCE7, 2CCE9, 2CD7B, 2CEBE, 2CE99","status":"derivada del contorno CAD"},{"label":"Extensión local Y","value":1.2,"unit":"m","source":"2CCDD, 2CD57, 2CCF5, 2CD99, 2CCE7, 2CCE9, 2CD7B, 2CEBE, 2CE99","status":"derivada del contorno CAD"},{"label":"Cota inferior relativa adoptada","value":-1.1,"unit":"m","source":"ZD1 / DZ-1","status":"documentada"},{"label":"Cota superior relativa adoptada","value":-1.0,"unit":"m","source":"ZD1 / DZ-1","status":"documentada / separación por material"}],"geometry":[{"label":"Extensión de la malla en X","value":1.352261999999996,"unit":"m","source":"Geometría releída del IFC; datum absoluto de proceso provisional","status":"derivado"},{"label":"Extensión de la malla en Y","value":1.3522620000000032,"unit":"m","source":"Geometría releída del IFC; datum absoluto de proceso provisional","status":"derivado"},{"label":"Extensión de la malla en Z","value":0.1,"unit":"m","source":"Geometría releída del IFC; datum absoluto de proceso provisional","status":"derivado"},{"label":"Cota inferior de visualización","value":285.0,"unit":"m","source":"Geometría releída del IFC; datum absoluto de proceso provisional","status":"derivado"},{"label":"Cota superior de visualización","value":285.1,"unit":"m","source":"Geometría releída del IFC; datum absoluto de proceso provisional","status":"derivado"}]} | [] | {"Cota inferior relativa (m)":-1.1,"Cota superior relativa (m)":-1.0,"Cero absoluto de visualización (m)":286.1,"Estado del cero absoluto":"Provisional","Criterio":"Las cotas relativas proceden del dibujo; la equivalencia absoluta no está confirmada."} | SUP-C28 | [] | ["C28"] | ZD1 / DZ-1 | ["2CCDD","2CD57","2CCF5","2CD99","2CCE7","2CCE9","2CD7B","2CEBE","2CE99"] | SUP-C28/Cimentación de soporte de tuberías C28 · capa de limpieza | {"boundingBoxM":{"min":[61.56443,49.807632,0.0],"max":[62.916692,51.159894,0.1]},"extentsM":[1.352262,1.352262,0.1],"meshSurfaceM2":3.36,"meshVolumeM3":0.144,"closedSolid":true,"basis":"Magnitudes de las mallas representadas, no cantidades certificadas de obra, compra o fabricación. Las partes pueden compartir superficies; no se suman como un despiece de materiales."} | {"profileId":"concrete_ha20","name":"Hormigón de limpieza HA-20","materialName":"Hormigón de limpieza HA-20","physicalMaterialStatus":"documentado","physicalMaterialSource":"Secciones del fabricante: capa de limpieza de 100 mm; nota 2CED5","appearanceStatus":"criterio_visual","appearanceBasis":"Interpretación visual del material documental; el acabado, tono y parámetros PBR no son una especificación contractual.","note":"La apariencia gráfica no modifica ni confirma la especificación física del material."} | {"elementId":"found_0904_53ade2fdc3ec07","ifcGuid":"3fI_A2P1LIa9QigEmxhxWx","ifcClass":"IfcSlab","buildingId":"process_plant","buildingName":"Zona de separación de aire","sourceDocumentId":"LHD2609-JG00100-20260904","sourceRepresentationKind":"foundation"} | {"profileId":"concrete_ha20","name":"Hormigón de limpieza HA-20","status":"criterio_visual","basis":"Interpretación visual del material documental; el acabado, tono y parámetros PBR no son una especificación contractual.","physicalMaterialUnchanged":true} |  | 2CCDD, 2CD57, 2CCF5, 2CD99, 2CCE7, 2CCE9, 2CD7B, 2CEBE, 2CE99 | Hormigón de limpieza HA-20 | -1.1 | -1 | 1.44 | 0.144 | Contornos y sección documentados por el fabricante | Hormigón de limpieza HA-20 | found_0904_53ade2fdc3ec07 | documentado | Secciones del fabricante: capa de limpieza de 100 mm; nota 2CED5 | 1.2 | 1.2 | concrete_ha20 | [0.721569,0.709804,0.658824] | 0.98
Cimentación de soporte de tuberías C29 · capa de limpieza | Hormigón de limpieza HA-20 | 1.35226 | 1.35226 | 0.1 | 285 | 285.1 | 3.36 | 0.144 | {"documentId":"LHD2609-JG00100-20260904","title":"Cimentaciones de equipos y pedestales del fabricante · revisión recibida 04/09/2026","date":"2026-09-04","sheet":"ZD1 / DZ-2","fileName":"LHD2609-JG00100_20260904.dwg","revisionCaveat":"Fecha de revisión tomada del nombre recibido; cajetines internos mantienen 02/07/2026 y algunos textos de plantilla.","sourceFileSha256":"b42eb027b7bc0b14c38d1d13514f4899b58a732aa8d0ba2ccf10fa2fc3192890"} | {"name":"Hormigón de limpieza HA-20","status":"documentado","source":"Secciones del fabricante: capa de limpieza de 100 mm; nota 2CED5"} | {"documented":[{"label":"Extensión local X","value":1.2,"unit":"m","source":"2CCDE, 2CD61, 2CCF6, 2CD9A, 2CCF1, 2CCEC, 2CD85, 2CEBF, 2CE9A","status":"derivada del contorno CAD"},{"label":"Extensión local Y","value":1.2,"unit":"m","source":"2CCDE, 2CD61, 2CCF6, 2CD9A, 2CCF1, 2CCEC, 2CD85, 2CEBF, 2CE9A","status":"derivada del contorno CAD"},{"label":"Cota inferior relativa adoptada","value":-1.1,"unit":"m","source":"ZD1 / DZ-2","status":"documentada"},{"label":"Cota superior relativa adoptada","value":-1.0,"unit":"m","source":"ZD1 / DZ-2","status":"documentada / separación por material"}],"geometry":[{"label":"Extensión de la malla en X","value":1.352261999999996,"unit":"m","source":"Geometría releída del IFC; datum absoluto de proceso provisional","status":"derivado"},{"label":"Extensión de la malla en Y","value":1.3522609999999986,"unit":"m","source":"Geometría releída del IFC; datum absoluto de proceso provisional","status":"derivado"},{"label":"Extensión de la malla en Z","value":0.1,"unit":"m","source":"Geometría releída del IFC; datum absoluto de proceso provisional","status":"derivado"},{"label":"Cota inferior de visualización","value":285.0,"unit":"m","source":"Geometría releída del IFC; datum absoluto de proceso provisional","status":"derivado"},{"label":"Cota superior de visualización","value":285.1,"unit":"m","source":"Geometría releída del IFC; datum absoluto de proceso provisional","status":"derivado"}]} | [] | {"Cota inferior relativa (m)":-1.1,"Cota superior relativa (m)":-1.0,"Cero absoluto de visualización (m)":286.1,"Estado del cero absoluto":"Provisional","Criterio":"Las cotas relativas proceden del dibujo; la equivalencia absoluta no está confirmada."} | SUP-C29 | [] | ["C29"] | ZD1 / DZ-2 | ["2CCDE","2CD61","2CCF6","2CD9A","2CCF1","2CCEC","2CD85","2CEBF","2CE9A"] | SUP-C29/Cimentación de soporte de tuberías C29 · capa de limpieza | {"boundingBoxM":{"min":[42.697898,48.59099,0.0],"max":[44.05016,49.943251,0.1]},"extentsM":[1.352262,1.352261,0.1],"meshSurfaceM2":3.36,"meshVolumeM3":0.144,"closedSolid":true,"basis":"Magnitudes de las mallas representadas, no cantidades certificadas de obra, compra o fabricación. Las partes pueden compartir superficies; no se suman como un despiece de materiales."} | {"profileId":"concrete_ha20","name":"Hormigón de limpieza HA-20","materialName":"Hormigón de limpieza HA-20","physicalMaterialStatus":"documentado","physicalMaterialSource":"Secciones del fabricante: capa de limpieza de 100 mm; nota 2CED5","appearanceStatus":"criterio_visual","appearanceBasis":"Interpretación visual del material documental; el acabado, tono y parámetros PBR no son una especificación contractual.","note":"La apariencia gráfica no modifica ni confirma la especificación física del material."} | {"elementId":"found_0904_8c7236d1a4a4d1","ifcGuid":"02UeiMxCXHUvCDg6LgdU1A","ifcClass":"IfcSlab","buildingId":"process_plant","buildingName":"Zona de separación de aire","sourceDocumentId":"LHD2609-JG00100-20260904","sourceRepresentationKind":"foundation"} | {"profileId":"concrete_ha20","name":"Hormigón de limpieza HA-20","status":"criterio_visual","basis":"Interpretación visual del material documental; el acabado, tono y parámetros PBR no son una especificación contractual.","physicalMaterialUnchanged":true} |  | 2CCDE, 2CD61, 2CCF6, 2CD9A, 2CCF1, 2CCEC, 2CD85, 2CEBF, 2CE9A | Hormigón de limpieza HA-20 | -1.1 | -1 | 1.44 | 0.144 | Contornos y sección documentados por el fabricante | Hormigón de limpieza HA-20 | found_0904_8c7236d1a4a4d1 | documentado | Secciones del fabricante: capa de limpieza de 100 mm; nota 2CED5 | 1.2 | 1.2 | concrete_ha20 | [0.721569,0.709804,0.658824] | 0.98
Cimentación de soporte de tuberías C30 · capa de limpieza | Hormigón de limpieza HA-20 | 1.35226 | 1.35226 | 0.1 | 285 | 285.1 | 3.36 | 0.144 | {"documentId":"LHD2609-JG00100-20260904","title":"Cimentaciones de equipos y pedestales del fabricante · revisión recibida 04/09/2026","date":"2026-09-04","sheet":"ZD1 / DZ-2","fileName":"LHD2609-JG00100_20260904.dwg","revisionCaveat":"Fecha de revisión tomada del nombre recibido; cajetines internos mantienen 02/07/2026 y algunos textos de plantilla.","sourceFileSha256":"b42eb027b7bc0b14c38d1d13514f4899b58a732aa8d0ba2ccf10fa2fc3192890"} | {"name":"Hormigón de limpieza HA-20","status":"documentado","source":"Secciones del fabricante: capa de limpieza de 100 mm; nota 2CED5"} | {"documented":[{"label":"Extensión local X","value":1.2,"unit":"m","source":"2CCDF, 2CD62, 2CCF7, 2CD9B, 2CCEF, 2CCF0, 2CD86, 2CEC0, 2CE9B","status":"derivada del contorno CAD"},{"label":"Extensión local Y","value":1.2,"unit":"m","source":"2CCDF, 2CD62, 2CCF7, 2CD9B, 2CCEF, 2CCF0, 2CD86, 2CEC0, 2CE9B","status":"derivada del contorno CAD"},{"label":"Cota inferior relativa adoptada","value":-1.1,"unit":"m","source":"ZD1 / DZ-2","status":"interpretación con conflicto conservado"},{"label":"Cota superior relativa adoptada","value":-1.0,"unit":"m","source":"ZD1 / DZ-2","status":"documentada / separación por material"}],"geometry":[{"label":"Extensión de la malla en X","value":1.352261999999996,"unit":"m","source":"Geometría releída del IFC; datum absoluto de proceso provisional","status":"derivado"},{"label":"Extensión de la malla en Y","value":1.352261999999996,"unit":"m","source":"Geometría releída del IFC; datum absoluto de proceso provisional","status":"derivado"},{"label":"Extensión de la malla en Z","value":0.1,"unit":"m","source":"Geometría releída del IFC; datum absoluto de proceso provisional","status":"derivado"},{"label":"Cota inferior de visualización","value":285.0,"unit":"m","source":"Geometría releída del IFC; datum absoluto de proceso provisional","status":"derivado"},{"label":"Cota superior de visualización","value":285.1,"unit":"m","source":"Geometría releída del IFC; datum absoluto de proceso provisional","status":"derivado"}]} | ["Identificador original HA-30 en columna de posición; C30 se infiere por secuencia. Se conserva el original y no se interpreta como material."] | {"Cota inferior relativa (m)":-1.1,"Cota superior relativa (m)":-1.0,"Cero absoluto de visualización (m)":286.1,"Estado del cero absoluto":"Provisional","Criterio":"Las cotas relativas proceden del dibujo; la equivalencia absoluta no está confirmada."} | SUP-C30 | [] | ["C30"] | ZD1 / DZ-2 | ["2CCDF","2CD62","2CCF7","2CD9B","2CCEF","2CCF0","2CD86","2CEC0","2CE9B"] | SUP-C30/Cimentación de soporte de tuberías C30 · capa de limpieza | {"boundingBoxM":{"min":[41.948776,43.142245,0.0],"max":[43.301038,44.494507,0.1]},"extentsM":[1.352262,1.352262,0.1],"meshSurfaceM2":3.36,"meshVolumeM3":0.144,"closedSolid":true,"basis":"Magnitudes de las mallas representadas, no cantidades certificadas de obra, compra o fabricación. Las partes pueden compartir superficies; no se suman como un despiece de materiales."} | {"profileId":"concrete_ha20","name":"Hormigón de limpieza HA-20","materialName":"Hormigón de limpieza HA-20","physicalMaterialStatus":"documentado","physicalMaterialSource":"Secciones del fabricante: capa de limpieza de 100 mm; nota 2CED5","appearanceStatus":"criterio_visual","appearanceBasis":"Interpretación visual del material documental; el acabado, tono y parámetros PBR no son una especificación contractual.","note":"La apariencia gráfica no modifica ni confirma la especificación física del material."} | {"elementId":"found_0904_5727c4827595c3","ifcGuid":"3ukT8L91fJCxb2bmHZMN6J","ifcClass":"IfcSlab","buildingId":"process_plant","buildingName":"Zona de separación de aire","sourceDocumentId":"LHD2609-JG00100-20260904","sourceRepresentationKind":"foundation"} | {"profileId":"concrete_ha20","name":"Hormigón de limpieza HA-20","status":"criterio_visual","basis":"Interpretación visual del material documental; el acabado, tono y parámetros PBR no son una especificación contractual.","physicalMaterialUnchanged":true} |  | 2CCDF, 2CD62, 2CCF7, 2CD9B, 2CCEF, 2CCF0, 2CD86, 2CEC0, 2CE9B | Hormigón de limpieza HA-20 | -1.1 | -1 | 1.44 | 0.144 | Sección y contornos del fabricante; incidencias conservadas | Hormigón de limpieza HA-20 | found_0904_5727c4827595c3 | documentado | Secciones del fabricante: capa de limpieza de 100 mm; nota 2CED5 | 1.2 | 1.2 | concrete_ha20 | [0.721569,0.709804,0.658824] | 0.98 | Identificador original HA-30 en columna de posición; C30 se infiere por secuencia. Se conserva el original y no se interpreta como material.
Cimentación de soporte de tuberías C31 · capa de limpieza | Hormigón de limpieza HA-20 | 1.35226 | 1.35226 | 0.1 | 285 | 285.1 | 3.36 | 0.144 | {"documentId":"LHD2609-JG00100-20260904","title":"Cimentaciones de equipos y pedestales del fabricante · revisión recibida 04/09/2026","date":"2026-09-04","sheet":"ZD1 / DZ-2","fileName":"LHD2609-JG00100_20260904.dwg","revisionCaveat":"Fecha de revisión tomada del nombre recibido; cajetines internos mantienen 02/07/2026 y algunos textos de plantilla.","sourceFileSha256":"b42eb027b7bc0b14c38d1d13514f4899b58a732aa8d0ba2ccf10fa2fc3192890"} | {"name":"Hormigón de limpieza HA-20","status":"documentado","source":"Secciones del fabricante: capa de limpieza de 100 mm; nota 2CED5"} | {"documented":[{"label":"Extensión local X","value":1.2,"unit":"m","source":"2CCE0, 2CD63, 2CCF8, 2CD9C, 2CCED, 2CCEE, 2CD87, 2CEC1, 2CE9C","status":"derivada del contorno CAD"},{"label":"Extensión local Y","value":1.2,"unit":"m","source":"2CCE0, 2CD63, 2CCF8, 2CD9C, 2CCED, 2CCEE, 2CD87, 2CEC1, 2CE9C","status":"derivada del contorno CAD"},{"label":"Cota inferior relativa adoptada","value":-1.1,"unit":"m","source":"ZD1 / DZ-2","status":"documentada"},{"label":"Cota superior relativa adoptada","value":-1.0,"unit":"m","source":"ZD1 / DZ-2","status":"documentada / separación por material"}],"geometry":[{"label":"Extensión de la malla en X","value":1.3522609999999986,"unit":"m","source":"Geometría releída del IFC; datum absoluto de proceso provisional","status":"derivado"},{"label":"Extensión de la malla en Y","value":1.3522609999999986,"unit":"m","source":"Geometría releída del IFC; datum absoluto de proceso provisional","status":"derivado"},{"label":"Extensión de la malla en Z","value":0.1,"unit":"m","source":"Geometría releída del IFC; datum absoluto de proceso provisional","status":"derivado"},{"label":"Cota inferior de visualización","value":285.0,"unit":"m","source":"Geometría releída del IFC; datum absoluto de proceso provisional","status":"derivado"},{"label":"Cota superior de visualización","value":285.1,"unit":"m","source":"Geometría releída del IFC; datum absoluto de proceso provisional","status":"derivado"}]} | [] | {"Cota inferior relativa (m)":-1.1,"Cota superior relativa (m)":-1.0,"Cero absoluto de visualización (m)":286.1,"Estado del cero absoluto":"Provisional","Criterio":"Las cotas relativas proceden del dibujo; la equivalencia absoluta no está confirmada."} | SUP-C31 | [] | ["C31"] | ZD1 / DZ-2 | ["2CCE0","2CD63","2CCF8","2CD9C","2CCED","2CCEE","2CD87","2CEC1","2CE9C"] | SUP-C31/Cimentación de soporte de tuberías C31 · capa de limpieza | {"boundingBoxM":{"min":[46.637106,47.140941,0.0],"max":[47.989367,48.493202,0.1]},"extentsM":[1.352261,1.352261,0.1],"meshSurfaceM2":3.36,"meshVolumeM3":0.144,"closedSolid":true,"basis":"Magnitudes de las mallas representadas, no cantidades certificadas de obra, compra o fabricación. Las partes pueden compartir superficies; no se suman como un despiece de materiales."} | {"profileId":"concrete_ha20","name":"Hormigón de limpieza HA-20","materialName":"Hormigón de limpieza HA-20","physicalMaterialStatus":"documentado","physicalMaterialSource":"Secciones del fabricante: capa de limpieza de 100 mm; nota 2CED5","appearanceStatus":"criterio_visual","appearanceBasis":"Interpretación visual del material documental; el acabado, tono y parámetros PBR no son una especificación contractual.","note":"La apariencia gráfica no modifica ni confirma la especificación física del material."} | {"elementId":"found_0904_6b04b25b393f1b","ifcGuid":"0p6RscqzTPOhpYup0RQwDN","ifcClass":"IfcSlab","buildingId":"process_plant","buildingName":"Zona de separación de aire","sourceDocumentId":"LHD2609-JG00100-20260904","sourceRepresentationKind":"foundation"} | {"profileId":"concrete_ha20","name":"Hormigón de limpieza HA-20","status":"criterio_visual","basis":"Interpretación visual del material documental; el acabado, tono y parámetros PBR no son una especificación contractual.","physicalMaterialUnchanged":true} |  | 2CCE0, 2CD63, 2CCF8, 2CD9C, 2CCED, 2CCEE, 2CD87, 2CEC1, 2CE9C | Hormigón de limpieza HA-20 | -1.1 | -1 | 1.44 | 0.144 | Contornos y sección documentados por el fabricante | Hormigón de limpieza HA-20 | found_0904_6b04b25b393f1b | documentado | Secciones del fabricante: capa de limpieza de 100 mm; nota 2CED5 | 1.2 | 1.2 | concrete_ha20 | [0.721569,0.709804,0.658824] | 0.98
Cimentación de soporte de tuberías C32 · capa de limpieza | Hormigón de limpieza HA-20 | 1.35226 | 1.35226 | 0.1 | 285 | 285.1 | 3.36 | 0.144 | {"documentId":"LHD2609-JG00100-20260904","title":"Cimentaciones de equipos y pedestales del fabricante · revisión recibida 04/09/2026","date":"2026-09-04","sheet":"ZD1 / DZ-2","fileName":"LHD2609-JG00100_20260904.dwg","revisionCaveat":"Fecha de revisión tomada del nombre recibido; cajetines internos mantienen 02/07/2026 y algunos textos de plantilla.","sourceFileSha256":"b42eb027b7bc0b14c38d1d13514f4899b58a732aa8d0ba2ccf10fa2fc3192890"} | {"name":"Hormigón de limpieza HA-20","status":"documentado","source":"Secciones del fabricante: capa de limpieza de 100 mm; nota 2CED5"} | {"documented":[{"label":"Extensión local X","value":1.2,"unit":"m","source":"2CCE1, 2CD64, 2CCF9, 2CD9D, 2CCEA, 2CCEB, 2CD88, 2CEC2, 2CE9D","status":"derivada del contorno CAD"},{"label":"Extensión local Y","value":1.2,"unit":"m","source":"2CCE1, 2CD64, 2CCF9, 2CD9D, 2CCEA, 2CCEB, 2CD88, 2CEC2, 2CE9D","status":"derivada del contorno CAD"},{"label":"Cota inferior relativa adoptada","value":-1.1,"unit":"m","source":"ZD1 / DZ-2","status":"documentada"},{"label":"Cota superior relativa adoptada","value":-1.0,"unit":"m","source":"ZD1 / DZ-2","status":"documentada / separación por material"}],"geometry":[{"label":"Extensión de la malla en X","value":1.3522609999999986,"unit":"m","source":"Geometría releída del IFC; datum absoluto de proceso provisional","status":"derivado"},{"label":"Extensión de la malla en Y","value":1.3522609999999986,"unit":"m","source":"Geometría releída del IFC; datum absoluto de proceso provisional","status":"derivado"},{"label":"Extensión de la malla en Z","value":0.1,"unit":"m","source":"Geometría releída del IFC; datum absoluto de proceso provisional","status":"derivado"},{"label":"Cota inferior de visualización","value":285.0,"unit":"m","source":"Geometría releída del IFC; datum absoluto de proceso provisional","status":"derivado"},{"label":"Cota superior de visualización","value":285.1,"unit":"m","source":"Geometría releída del IFC; datum absoluto de proceso provisional","status":"derivado"}]} | [] | {"Cota inferior relativa (m)":-1.1,"Cota superior relativa (m)":-1.0,"Cero absoluto de visualización (m)":286.1,"Estado del cero absoluto":"Provisional","Criterio":"Las cotas relativas proceden del dibujo; la equivalencia absoluta no está confirmada."} | SUP-C32 | [] | ["C32"] | ZD1 / DZ-2 | ["2CCE1","2CD64","2CCF9","2CD9D","2CCEA","2CCEB","2CD88","2CEC2","2CE9D"] | SUP-C32/Cimentación de soporte de tuberías C32 · capa de limpieza | {"boundingBoxM":{"min":[46.282976,44.565171,0.0],"max":[47.635237,45.917432,0.1]},"extentsM":[1.352261,1.352261,0.1],"meshSurfaceM2":3.359998,"meshVolumeM3":0.144,"closedSolid":true,"basis":"Magnitudes de las mallas representadas, no cantidades certificadas de obra, compra o fabricación. Las partes pueden compartir superficies; no se suman como un despiece de materiales."} | {"profileId":"concrete_ha20","name":"Hormigón de limpieza HA-20","materialName":"Hormigón de limpieza HA-20","physicalMaterialStatus":"documentado","physicalMaterialSource":"Secciones del fabricante: capa de limpieza de 100 mm; nota 2CED5","appearanceStatus":"criterio_visual","appearanceBasis":"Interpretación visual del material documental; el acabado, tono y parámetros PBR no son una especificación contractual.","note":"La apariencia gráfica no modifica ni confirma la especificación física del material."} | {"elementId":"found_0904_d9b4e4f8e5239d","ifcGuid":"2sT4YaGHPVLAarx9pytsfU","ifcClass":"IfcSlab","buildingId":"process_plant","buildingName":"Zona de separación de aire","sourceDocumentId":"LHD2609-JG00100-20260904","sourceRepresentationKind":"foundation"} | {"profileId":"concrete_ha20","name":"Hormigón de limpieza HA-20","status":"criterio_visual","basis":"Interpretación visual del material documental; el acabado, tono y parámetros PBR no son una especificación contractual.","physicalMaterialUnchanged":true} |  | 2CCE1, 2CD64, 2CCF9, 2CD9D, 2CCEA, 2CCEB, 2CD88, 2CEC2, 2CE9D | Hormigón de limpieza HA-20 | -1.1 | -1 | 1.44 | 0.144 | Contornos y sección documentados por el fabricante | Hormigón de limpieza HA-20 | found_0904_d9b4e4f8e5239d | documentado | Secciones del fabricante: capa de limpieza de 100 mm; nota 2CED5 | 1.2 | 1.2 | concrete_ha20 | [0.721569,0.709804,0.658824] | 0.98
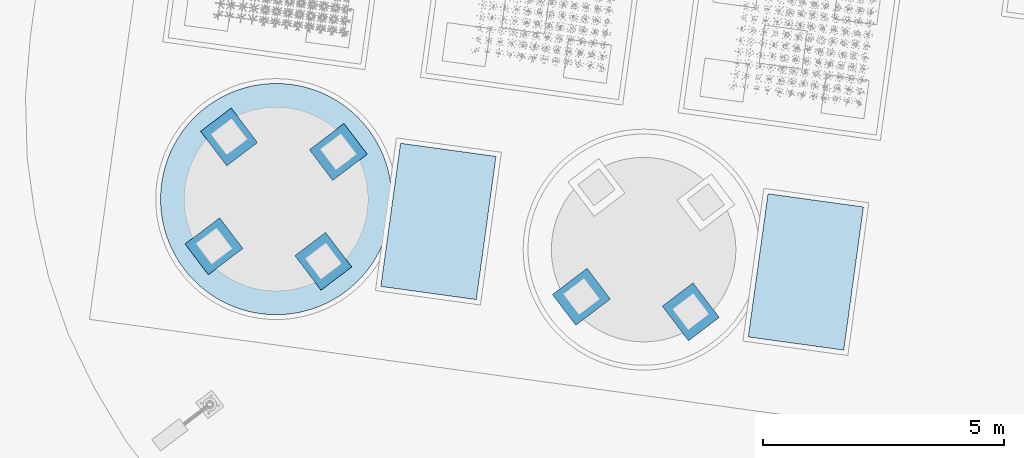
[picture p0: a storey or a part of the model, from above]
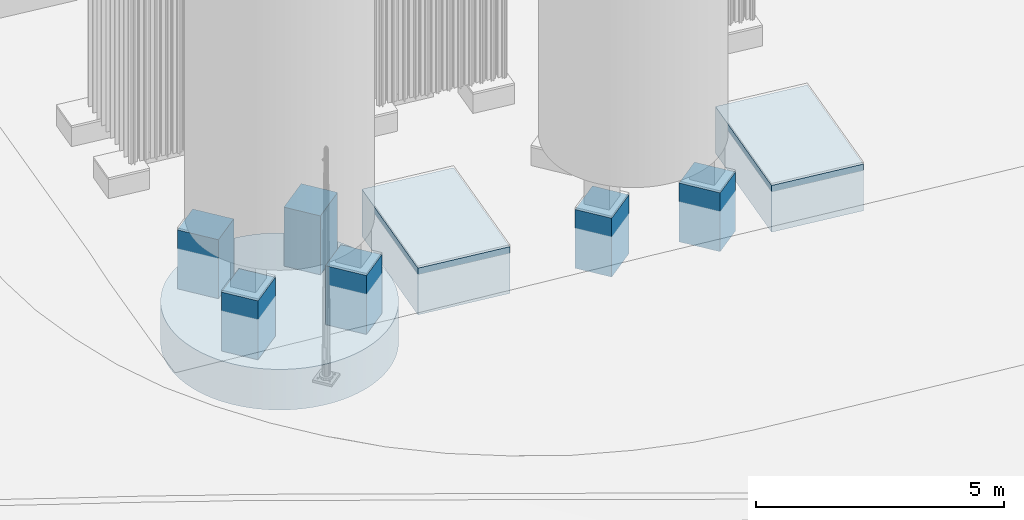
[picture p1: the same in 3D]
Properties of the parts of a building model (IFC4), part 110 of 134

# IfcSlab: Cimentación industrial (108)
Name | Material | Extensión de la malla en X (m) = ExtensionX (m) | Extensión de la malla en Y (m) = ExtensionY (m) | Extensión de la malla en Z (m) = ExtensionZ (m) = Espesor o altura real de sección (m) | Cota inferior de visualización (m) | Cota superior de visualización (m) | SuperficieDeLaMalla (m2) | VolumenGeometrico (m3) | JH_InformacionBIM, source = DocumentoFuente | material | dimensions | issues = IncidenciasPendientes | positioning = PosicionYEstado | assemblyId = Conjunto de cimentación | equipmentIds | supportPositionIds | sectionRef = Sección de referencia | sourceCadHandles | stableElementKey | geometryMetrics | materialAppearance | visualizationIdentity | appearance | Equipos asociados | Identificadores CAD de referencia | JH_Trazabilidad, Material = name | Cota inferior relativa (m) = Cota inferior relativa adoptada (m) | Cota superior relativa (m) = Cota superior relativa adoptada (m) | Área de planta (m²) | Volumen geométrico (m³) | Estado de la geometría | Acabado de visualización = Acabado | Identificador | status | JH_EvidenciaDeMaterial, source | Extensión local X (m) | Extensión local Y (m) | Perfil | ColorRGB | Rugosidad | Incidencias de origen
Cimentación de soporte de tuberías C33 · capa de limpieza | Hormigón de limpieza HA-20 | 1.35226 | 1.35226 | 0.1 | 285 | 285.1 | 3.36 | 0.144 | {"documentId":"LHD2609-JG00100-20260904","title":"Cimentaciones de equipos y pedestales del fabricante · revisión recibida 04/09/2026","date":"2026-09-04","sheet":"ZD1 / DZ-2","fileName":"LHD2609-JG00100_20260904.dwg","revisionCaveat":"Fecha de revisión tomada del nombre recibido; cajetines internos mantienen 02/07/2026 y algunos textos de plantilla.","sourceFileSha256":"b42eb027b7bc0b14c38d1d13514f4899b58a732aa8d0ba2ccf10fa2fc3192890"} | {"name":"Hormigón de limpieza HA-20","status":"documentado","source":"Secciones del fabricante: capa de limpieza de 100 mm; nota 2CED5"} | {"documented":[{"label":"Extensión local X","value":1.2,"unit":"m","source":"2CD0A, 2CD58, 2CD22, 2CD9E, 2CD13, 2CD14, 2CD89, 2CEC3, 2CE9E","status":"derivada del contorno CAD"},{"label":"Extensión local Y","value":1.2,"unit":"m","source":"2CD0A, 2CD58, 2CD22, 2CD9E, 2CD13, 2CD14, 2CD89, 2CEC3, 2CE9E","status":"derivada del contorno CAD"},{"label":"Cota inferior relativa adoptada","value":-1.1,"unit":"m","source":"ZD1 / DZ-2","status":"documentada"},{"label":"Cota superior relativa adoptada","value":-1.0,"unit":"m","source":"ZD1 / DZ-2","status":"documentada / separación por material"}],"geometry":[{"label":"Extensión de la malla en X","value":1.3522609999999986,"unit":"m","source":"Geometría releída del IFC; datum absoluto de proceso provisional","status":"derivado"},{"label":"Extensión de la malla en Y","value":1.3522620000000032,"unit":"m","source":"Geometría releída del IFC; datum absoluto de proceso provisional","status":"derivado"},{"label":"Extensión de la malla en Z","value":0.1,"unit":"m","source":"Geometría releída del IFC; datum absoluto de proceso provisional","status":"derivado"},{"label":"Cota inferior de visualización","value":285.0,"unit":"m","source":"Geometría releída del IFC; datum absoluto de proceso provisional","status":"derivado"},{"label":"Cota superior de visualización","value":285.1,"unit":"m","source":"Geometría releída del IFC; datum absoluto de proceso provisional","status":"derivado"}]} | [] | {"Cota inferior relativa (m)":-1.1,"Cota superior relativa (m)":-1.0,"Cero absoluto de visualización (m)":286.1,"Estado del cero absoluto":"Provisional","Criterio":"Las cotas relativas proceden del dibujo; la equivalencia absoluta no está confirmada."} | SUP-C33 | [] | ["C33"] | ZD1 / DZ-2 | ["2CD0A","2CD58","2CD22","2CD9E","2CD13","2CD14","2CD89","2CEC3","2CE9E"] | SUP-C33/Cimentación de soporte de tuberías C33 · capa de limpieza | {"boundingBoxM":{"min":[50.590516,48.363867,0.0],"max":[51.942777,49.716129,0.1]},"extentsM":[1.352261,1.352262,0.1],"meshSurfaceM2":3.36,"meshVolumeM3":0.144,"closedSolid":true,"basis":"Magnitudes de las mallas representadas, no cantidades certificadas de obra, compra o fabricación. Las partes pueden compartir superficies; no se suman como un despiece de materiales."} | {"profileId":"concrete_ha20","name":"Hormigón de limpieza HA-20","materialName":"Hormigón de limpieza HA-20","physicalMaterialStatus":"documentado","physicalMaterialSource":"Secciones del fabricante: capa de limpieza de 100 mm; nota 2CED5","appearanceStatus":"criterio_visual","appearanceBasis":"Interpretación visual del material documental; el acabado, tono y parámetros PBR no son una especificación contractual.","note":"La apariencia gráfica no modifica ni confirma la especificación física del material."} | {"elementId":"found_0904_b21df6209cd2c1","ifcGuid":"02Idn3x3rOM9AHBQITMfwg","ifcClass":"IfcSlab","buildingId":"process_plant","buildingName":"Zona de separación de aire","sourceDocumentId":"LHD2609-JG00100-20260904","sourceRepresentationKind":"foundation"} | {"profileId":"concrete_ha20","name":"Hormigón de limpieza HA-20","status":"criterio_visual","basis":"Interpretación visual del material documental; el acabado, tono y parámetros PBR no son una especificación contractual.","physicalMaterialUnchanged":true} |  | 2CD0A, 2CD58, 2CD22, 2CD9E, 2CD13, 2CD14, 2CD89, 2CEC3, 2CE9E | Hormigón de limpieza HA-20 | -1.1 | -1 | 1.44 | 0.144 | Contornos y sección documentados por el fabricante | Hormigón de limpieza HA-20 | found_0904_b21df6209cd2c1 | documentado | Secciones del fabricante: capa de limpieza de 100 mm; nota 2CED5 | 1.2 | 1.2 | concrete_ha20 | [0.721569,0.709804,0.658824] | 0.98
Cimentación de soporte de tuberías C34 · capa de limpieza | Hormigón de limpieza HA-20 | 1.35226 | 1.35226 | 0.1 | 285 | 285.1 | 3.36 | 0.144 | {"documentId":"LHD2609-JG00100-20260904","title":"Cimentaciones de equipos y pedestales del fabricante · revisión recibida 04/09/2026","date":"2026-09-04","sheet":"ZD1 / DZ-2","fileName":"LHD2609-JG00100_20260904.dwg","revisionCaveat":"Fecha de revisión tomada del nombre recibido; cajetines internos mantienen 02/07/2026 y algunos textos de plantilla.","sourceFileSha256":"b42eb027b7bc0b14c38d1d13514f4899b58a732aa8d0ba2ccf10fa2fc3192890"} | {"name":"Hormigón de limpieza HA-20","status":"documentado","source":"Secciones del fabricante: capa de limpieza de 100 mm; nota 2CED5"} | {"documented":[{"label":"Extensión local X","value":1.2,"unit":"m","source":"2CD0B, 2CD66, 2CD23, 2CD9F, 2CD12, 2CD15, 2CD8A, 2CEC4, 2CE9F","status":"derivada del contorno CAD"},{"label":"Extensión local Y","value":1.2,"unit":"m","source":"2CD0B, 2CD66, 2CD23, 2CD9F, 2CD12, 2CD15, 2CD8A, 2CEC4, 2CE9F","status":"derivada del contorno CAD"},{"label":"Cota inferior relativa adoptada","value":-1.1,"unit":"m","source":"ZD1 / DZ-2","status":"documentada"},{"label":"Cota superior relativa adoptada","value":-1.0,"unit":"m","source":"ZD1 / DZ-2","status":"documentada / separación por material"}],"geometry":[{"label":"Extensión de la malla en X","value":1.3522609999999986,"unit":"m","source":"Geometría releída del IFC; datum absoluto de proceso provisional","status":"derivado"},{"label":"Extensión de la malla en Y","value":1.3522609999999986,"unit":"m","source":"Geometría releída del IFC; datum absoluto de proceso provisional","status":"derivado"},{"label":"Extensión de la malla en Z","value":0.1,"unit":"m","source":"Geometría releída del IFC; datum absoluto de proceso provisional","status":"derivado"},{"label":"Cota inferior de visualización","value":285.0,"unit":"m","source":"Geometría releída del IFC; datum absoluto de proceso provisional","status":"derivado"},{"label":"Cota superior de visualización","value":285.1,"unit":"m","source":"Geometría releída del IFC; datum absoluto de proceso provisional","status":"derivado"}]} | [] | {"Cota inferior relativa (m)":-1.1,"Cota superior relativa (m)":-1.0,"Cero absoluto de visualización (m)":286.1,"Estado del cero absoluto":"Provisional","Criterio":"Las cotas relativas proceden del dibujo; la equivalencia absoluta no está confirmada."} | SUP-C34 | [] | ["C34"] | ZD1 / DZ-2 | ["2CD0B","2CD66","2CD23","2CD9F","2CD12","2CD15","2CD8A","2CEC4","2CE9F"] | SUP-C34/Cimentación de soporte de tuberías C34 · capa de limpieza | {"boundingBoxM":{"min":[59.485631,44.415523,0.0],"max":[60.837892,45.767784,0.1]},"extentsM":[1.352261,1.352261,0.1],"meshSurfaceM2":3.36,"meshVolumeM3":0.144,"closedSolid":true,"basis":"Magnitudes de las mallas representadas, no cantidades certificadas de obra, compra o fabricación. Las partes pueden compartir superficies; no se suman como un despiece de materiales."} | {"profileId":"concrete_ha20","name":"Hormigón de limpieza HA-20","materialName":"Hormigón de limpieza HA-20","physicalMaterialStatus":"documentado","physicalMaterialSource":"Secciones del fabricante: capa de limpieza de 100 mm; nota 2CED5","appearanceStatus":"criterio_visual","appearanceBasis":"Interpretación visual del material documental; el acabado, tono y parámetros PBR no son una especificación contractual.","note":"La apariencia gráfica no modifica ni confirma la especificación física del material."} | {"elementId":"found_0904_e253a73415e685","ifcGuid":"35WvishtTRFBR3smzNkuWS","ifcClass":"IfcSlab","buildingId":"process_plant","buildingName":"Zona de separación de aire","sourceDocumentId":"LHD2609-JG00100-20260904","sourceRepresentationKind":"foundation"} | {"profileId":"concrete_ha20","name":"Hormigón de limpieza HA-20","status":"criterio_visual","basis":"Interpretación visual del material documental; el acabado, tono y parámetros PBR no son una especificación contractual.","physicalMaterialUnchanged":true} |  | 2CD0B, 2CD66, 2CD23, 2CD9F, 2CD12, 2CD15, 2CD8A, 2CEC4, 2CE9F | Hormigón de limpieza HA-20 | -1.1 | -1 | 1.44 | 0.144 | Contornos y sección documentados por el fabricante | Hormigón de limpieza HA-20 | found_0904_e253a73415e685 | documentado | Secciones del fabricante: capa de limpieza de 100 mm; nota 2CED5 | 1.2 | 1.2 | concrete_ha20 | [0.721569,0.709804,0.658824] | 0.98
Cimentación de soporte de tuberías C35 · capa de limpieza | Hormigón de limpieza HA-20 | 1.35226 | 1.35226 | 0.1 | 285 | 285.1 | 3.36 | 0.144 | {"documentId":"LHD2609-JG00100-20260904","title":"Cimentaciones de equipos y pedestales del fabricante · revisión recibida 04/09/2026","date":"2026-09-04","sheet":"ZD1 / DZ-2","fileName":"LHD2609-JG00100_20260904.dwg","revisionCaveat":"Fecha de revisión tomada del nombre recibido; cajetines internos mantienen 02/07/2026 y algunos textos de plantilla.","sourceFileSha256":"b42eb027b7bc0b14c38d1d13514f4899b58a732aa8d0ba2ccf10fa2fc3192890"} | {"name":"Hormigón de limpieza HA-20","status":"documentado","source":"Secciones del fabricante: capa de limpieza de 100 mm; nota 2CED5"} | {"documented":[{"label":"Extensión local X","value":1.2,"unit":"m","source":"2CD0C, 2CD65, 2CD24, 2CDA0, 2CD16, 2CD18, 2CD8B, 2CEC5, 2CEA0","status":"derivada del contorno CAD"},{"label":"Extensión local Y","value":1.2,"unit":"m","source":"2CD0C, 2CD65, 2CD24, 2CDA0, 2CD16, 2CD18, 2CD8B, 2CEC5, 2CEA0","status":"derivada del contorno CAD"},{"label":"Cota inferior relativa adoptada","value":-1.1,"unit":"m","source":"ZD1 / DZ-2","status":"interpretación con conflicto conservado"},{"label":"Cota superior relativa adoptada","value":-1.0,"unit":"m","source":"ZD1 / DZ-2","status":"documentada / separación por material"}],"geometry":[{"label":"Extensión de la malla en X","value":1.3522609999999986,"unit":"m","source":"Geometría releída del IFC; datum absoluto de proceso provisional","status":"derivado"},{"label":"Extensión de la malla en Y","value":1.352261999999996,"unit":"m","source":"Geometría releída del IFC; datum absoluto de proceso provisional","status":"derivado"},{"label":"Extensión de la malla en Z","value":0.1,"unit":"m","source":"Geometría releída del IFC; datum absoluto de proceso provisional","status":"derivado"},{"label":"Cota inferior de visualización","value":285.0,"unit":"m","source":"Geometría releída del IFC; datum absoluto de proceso provisional","status":"derivado"},{"label":"Cota superior de visualización","value":285.1,"unit":"m","source":"Geometría releída del IFC; datum absoluto de proceso provisional","status":"derivado"}]} | ["Identificador original HA-35 en columna de posición; C35 se infiere por secuencia. Se conserva el original y no se interpreta como material."] | {"Cota inferior relativa (m)":-1.1,"Cota superior relativa (m)":-1.0,"Cero absoluto de visualización (m)":286.1,"Estado del cero absoluto":"Provisional","Criterio":"Las cotas relativas proceden del dibujo; la equivalencia absoluta no está confirmada."} | SUP-C35 | [] | ["C35"] | ZD1 / DZ-2 | ["2CD0C","2CD65","2CD24","2CDA0","2CD16","2CD18","2CD8B","2CEC5","2CEA0"] | SUP-C35/Cimentación de soporte de tuberías C35 · capa de limpieza | {"boundingBoxM":{"min":[60.426778,44.286129,0.0],"max":[61.779039,45.638391,0.1]},"extentsM":[1.352261,1.352262,0.1],"meshSurfaceM2":3.36,"meshVolumeM3":0.144,"closedSolid":true,"basis":"Magnitudes de las mallas representadas, no cantidades certificadas de obra, compra o fabricación. Las partes pueden compartir superficies; no se suman como un despiece de materiales."} | {"profileId":"concrete_ha20","name":"Hormigón de limpieza HA-20","materialName":"Hormigón de limpieza HA-20","physicalMaterialStatus":"documentado","physicalMaterialSource":"Secciones del fabricante: capa de limpieza de 100 mm; nota 2CED5","appearanceStatus":"criterio_visual","appearanceBasis":"Interpretación visual del material documental; el acabado, tono y parámetros PBR no son una especificación contractual.","note":"La apariencia gráfica no modifica ni confirma la especificación física del material."} | {"elementId":"found_0904_b1dc0edb3fb56b","ifcGuid":"21uygB$q5GL8jDzX8lAGvI","ifcClass":"IfcSlab","buildingId":"process_plant","buildingName":"Zona de separación de aire","sourceDocumentId":"LHD2609-JG00100-20260904","sourceRepresentationKind":"foundation"} | {"profileId":"concrete_ha20","name":"Hormigón de limpieza HA-20","status":"criterio_visual","basis":"Interpretación visual del material documental; el acabado, tono y parámetros PBR no son una especificación contractual.","physicalMaterialUnchanged":true} |  | 2CD0C, 2CD65, 2CD24, 2CDA0, 2CD16, 2CD18, 2CD8B, 2CEC5, 2CEA0 | Hormigón de limpieza HA-20 | -1.1 | -1 | 1.44 | 0.144 | Sección y contornos del fabricante; incidencias conservadas | Hormigón de limpieza HA-20 | found_0904_b1dc0edb3fb56b | documentado | Secciones del fabricante: capa de limpieza de 100 mm; nota 2CED5 | 1.2 | 1.2 | concrete_ha20 | [0.721569,0.709804,0.658824] | 0.98 | Identificador original HA-35 en columna de posición; C35 se infiere por secuencia. Se conserva el original y no se interpreta como material.
Cimentación de soporte de tuberías C36 · capa de limpieza | Hormigón de limpieza HA-20 | 1.35226 | 1.35226 | 0.1 | 285 | 285.1 | 3.36 | 0.144 | {"documentId":"LHD2609-JG00100-20260904","title":"Cimentaciones de equipos y pedestales del fabricante · revisión recibida 04/09/2026","date":"2026-09-04","sheet":"ZD1 / DZ-1","fileName":"LHD2609-JG00100_20260904.dwg","revisionCaveat":"Fecha de revisión tomada del nombre recibido; cajetines internos mantienen 02/07/2026 y algunos textos de plantilla.","sourceFileSha256":"b42eb027b7bc0b14c38d1d13514f4899b58a732aa8d0ba2ccf10fa2fc3192890"} | {"name":"Hormigón de limpieza HA-20","status":"documentado","source":"Secciones del fabricante: capa de limpieza de 100 mm; nota 2CED5"} | {"documented":[{"label":"Extensión local X","value":1.2,"unit":"m","source":"2CD0D, 2CD59, 2CD25, 2CDA1, 2CD17, 2CD19, 2CD7C, 2CEC6, 2CEA1","status":"derivada del contorno CAD"},{"label":"Extensión local Y","value":1.2,"unit":"m","source":"2CD0D, 2CD59, 2CD25, 2CDA1, 2CD17, 2CD19, 2CD7C, 2CEC6, 2CEA1","status":"derivada del contorno CAD"},{"label":"Cota inferior relativa adoptada","value":-1.1,"unit":"m","source":"ZD1 / DZ-1","status":"documentada"},{"label":"Cota superior relativa adoptada","value":-1.0,"unit":"m","source":"ZD1 / DZ-1","status":"documentada / separación por material"}],"geometry":[{"label":"Extensión de la malla en X","value":1.3522620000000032,"unit":"m","source":"Geometría releída del IFC; datum absoluto de proceso provisional","status":"derivado"},{"label":"Extensión de la malla en Y","value":1.3522609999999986,"unit":"m","source":"Geometría releída del IFC; datum absoluto de proceso provisional","status":"derivado"},{"label":"Extensión de la malla en Z","value":0.1,"unit":"m","source":"Geometría releída del IFC; datum absoluto de proceso provisional","status":"derivado"},{"label":"Cota inferior de visualización","value":285.0,"unit":"m","source":"Geometría releída del IFC; datum absoluto de proceso provisional","status":"derivado"},{"label":"Cota superior de visualización","value":285.1,"unit":"m","source":"Geometría releída del IFC; datum absoluto de proceso provisional","status":"derivado"}]} | [] | {"Cota inferior relativa (m)":-1.1,"Cota superior relativa (m)":-1.0,"Cero absoluto de visualización (m)":286.1,"Estado del cero absoluto":"Provisional","Criterio":"Las cotas relativas proceden del dibujo; la equivalencia absoluta no está confirmada."} | SUP-C36 | [] | ["C36"] | ZD1 / DZ-1 | ["2CD0D","2CD59","2CD25","2CDA1","2CD17","2CD19","2CD7C","2CEC6","2CEA1"] | SUP-C36/Cimentación de soporte de tuberías C36 · capa de limpieza | {"boundingBoxM":{"min":[58.948207,43.076241,0.0],"max":[60.300469,44.428502,0.1]},"extentsM":[1.352262,1.352261,0.1],"meshSurfaceM2":3.36,"meshVolumeM3":0.144,"closedSolid":true,"basis":"Magnitudes de las mallas representadas, no cantidades certificadas de obra, compra o fabricación. Las partes pueden compartir superficies; no se suman como un despiece de materiales."} | {"profileId":"concrete_ha20","name":"Hormigón de limpieza HA-20","materialName":"Hormigón de limpieza HA-20","physicalMaterialStatus":"documentado","physicalMaterialSource":"Secciones del fabricante: capa de limpieza de 100 mm; nota 2CED5","appearanceStatus":"criterio_visual","appearanceBasis":"Interpretación visual del material documental; el acabado, tono y parámetros PBR no son una especificación contractual.","note":"La apariencia gráfica no modifica ni confirma la especificación física del material."} | {"elementId":"found_0904_90e56725701b2a","ifcGuid":"27uGfLFJHO$BAVeHDwcjE5","ifcClass":"IfcSlab","buildingId":"process_plant","buildingName":"Zona de separación de aire","sourceDocumentId":"LHD2609-JG00100-20260904","sourceRepresentationKind":"foundation"} | {"profileId":"concrete_ha20","name":"Hormigón de limpieza HA-20","status":"criterio_visual","basis":"Interpretación visual del material documental; el acabado, tono y parámetros PBR no son una especificación contractual.","physicalMaterialUnchanged":true} |  | 2CD0D, 2CD59, 2CD25, 2CDA1, 2CD17, 2CD19, 2CD7C, 2CEC6, 2CEA1 | Hormigón de limpieza HA-20 | -1.1 | -1 | 1.44 | 0.144 | Contornos y sección documentados por el fabricante | Hormigón de limpieza HA-20 | found_0904_90e56725701b2a | documentado | Secciones del fabricante: capa de limpieza de 100 mm; nota 2CED5 | 1.2 | 1.2 | concrete_ha20 | [0.721569,0.709804,0.658824] | 0.98
Cimentación de soporte de tuberías C37 · capa de limpieza | Hormigón de limpieza HA-20 | 1.35226 | 1.35226 | 0.1 | 285 | 285.1 | 3.36 | 0.144 | {"documentId":"LHD2609-JG00100-20260904","title":"Cimentaciones de equipos y pedestales del fabricante · revisión recibida 04/09/2026","date":"2026-09-04","sheet":"ZD1 / DZ-1","fileName":"LHD2609-JG00100_20260904.dwg","revisionCaveat":"Fecha de revisión tomada del nombre recibido; cajetines internos mantienen 02/07/2026 y algunos textos de plantilla.","sourceFileSha256":"b42eb027b7bc0b14c38d1d13514f4899b58a732aa8d0ba2ccf10fa2fc3192890"} | {"name":"Hormigón de limpieza HA-20","status":"documentado","source":"Secciones del fabricante: capa de limpieza de 100 mm; nota 2CED5"} | {"documented":[{"label":"Extensión local X","value":1.2,"unit":"m","source":"2CD0E, 2CD5A, 2CD26, 2CDA2, 2CD21, 2CD1C, 2CD7D, 2CEC7, 2CEA2","status":"derivada del contorno CAD"},{"label":"Extensión local Y","value":1.2,"unit":"m","source":"2CD0E, 2CD5A, 2CD26, 2CDA2, 2CD21, 2CD1C, 2CD7D, 2CEC7, 2CEA2","status":"derivada del contorno CAD"},{"label":"Cota inferior relativa adoptada","value":-1.1,"unit":"m","source":"ZD1 / DZ-1","status":"documentada"},{"label":"Cota superior relativa adoptada","value":-1.0,"unit":"m","source":"ZD1 / DZ-1","status":"documentada / separación por material"}],"geometry":[{"label":"Extensión de la malla en X","value":1.3522620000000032,"unit":"m","source":"Geometría releída del IFC; datum absoluto de proceso provisional","status":"derivado"},{"label":"Extensión de la malla en Y","value":1.3522610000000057,"unit":"m","source":"Geometría releída del IFC; datum absoluto de proceso provisional","status":"derivado"},{"label":"Extensión de la malla en Z","value":0.1,"unit":"m","source":"Geometría releída del IFC; datum absoluto de proceso provisional","status":"derivado"},{"label":"Cota inferior de visualización","value":285.0,"unit":"m","source":"Geometría releída del IFC; datum absoluto de proceso provisional","status":"derivado"},{"label":"Cota superior de visualización","value":285.1,"unit":"m","source":"Geometría releída del IFC; datum absoluto de proceso provisional","status":"derivado"}]} | [] | {"Cota inferior relativa (m)":-1.1,"Cota superior relativa (m)":-1.0,"Cero absoluto de visualización (m)":286.1,"Estado del cero absoluto":"Provisional","Criterio":"Las cotas relativas proceden del dibujo; la equivalencia absoluta no está confirmada."} | SUP-C37 | [] | ["C37"] | ZD1 / DZ-1 | ["2CD0E","2CD5A","2CD26","2CDA2","2CD21","2CD1C","2CD7D","2CEC7","2CEA2"] | SUP-C37/Cimentación de soporte de tuberías C37 · capa de limpieza | {"boundingBoxM":{"min":[60.533296,42.858315,0.0],"max":[61.885558,44.210576,0.1]},"extentsM":[1.352262,1.352261,0.1],"meshSurfaceM2":3.359999,"meshVolumeM3":0.144,"closedSolid":true,"basis":"Magnitudes de las mallas representadas, no cantidades certificadas de obra, compra o fabricación. Las partes pueden compartir superficies; no se suman como un despiece de materiales."} | {"profileId":"concrete_ha20","name":"Hormigón de limpieza HA-20","materialName":"Hormigón de limpieza HA-20","physicalMaterialStatus":"documentado","physicalMaterialSource":"Secciones del fabricante: capa de limpieza de 100 mm; nota 2CED5","appearanceStatus":"criterio_visual","appearanceBasis":"Interpretación visual del material documental; el acabado, tono y parámetros PBR no son una especificación contractual.","note":"La apariencia gráfica no modifica ni confirma la especificación física del material."} | {"elementId":"found_0904_4533981561c983","ifcGuid":"0fZOwpYDjU79R0di9mRgQu","ifcClass":"IfcSlab","buildingId":"process_plant","buildingName":"Zona de separación de aire","sourceDocumentId":"LHD2609-JG00100-20260904","sourceRepresentationKind":"foundation"} | {"profileId":"concrete_ha20","name":"Hormigón de limpieza HA-20","status":"criterio_visual","basis":"Interpretación visual del material documental; el acabado, tono y parámetros PBR no son una especificación contractual.","physicalMaterialUnchanged":true} |  | 2CD0E, 2CD5A, 2CD26, 2CDA2, 2CD21, 2CD1C, 2CD7D, 2CEC7, 2CEA2 | Hormigón de limpieza HA-20 | -1.1 | -1 | 1.44 | 0.144 | Contornos y sección documentados por el fabricante | Hormigón de limpieza HA-20 | found_0904_4533981561c983 | documentado | Secciones del fabricante: capa de limpieza de 100 mm; nota 2CED5 | 1.2 | 1.2 | concrete_ha20 | [0.721569,0.709804,0.658824] | 0.98
Cimentación de soporte de tuberías C38 · capa de limpieza | Hormigón de limpieza HA-20 | 1.35226 | 1.35226 | 0.1 | 285 | 285.1 | 3.36 | 0.144 | {"documentId":"LHD2609-JG00100-20260904","title":"Cimentaciones de equipos y pedestales del fabricante · revisión recibida 04/09/2026","date":"2026-09-04","sheet":"ZD1 / DZ-1","fileName":"LHD2609-JG00100_20260904.dwg","revisionCaveat":"Fecha de revisión tomada del nombre recibido; cajetines internos mantienen 02/07/2026 y algunos textos de plantilla.","sourceFileSha256":"b42eb027b7bc0b14c38d1d13514f4899b58a732aa8d0ba2ccf10fa2fc3192890"} | {"name":"Hormigón de limpieza HA-20","status":"documentado","source":"Secciones del fabricante: capa de limpieza de 100 mm; nota 2CED5"} | {"documented":[{"label":"Extensión local X","value":1.2,"unit":"m","source":"2CD0F, 2CD5B, 2CD27, 2CDA3, 2CD1F, 2CD20, 2CD7E, 2CEC8, 2CEA3","status":"derivada del contorno CAD"},{"label":"Extensión local Y","value":1.2,"unit":"m","source":"2CD0F, 2CD5B, 2CD27, 2CDA3, 2CD1F, 2CD20, 2CD7E, 2CEC8, 2CEA3","status":"derivada del contorno CAD"},{"label":"Cota inferior relativa adoptada","value":-1.1,"unit":"m","source":"ZD1 / DZ-1","status":"documentada"},{"label":"Cota superior relativa adoptada","value":-1.0,"unit":"m","source":"ZD1 / DZ-1","status":"documentada / separación por material"}],"geometry":[{"label":"Extensión de la malla en X","value":1.3522620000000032,"unit":"m","source":"Geometría releída del IFC; datum absoluto de proceso provisional","status":"derivado"},{"label":"Extensión de la malla en Y","value":1.3522609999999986,"unit":"m","source":"Geometría releída del IFC; datum absoluto de proceso provisional","status":"derivado"},{"label":"Extensión de la malla en Z","value":0.1,"unit":"m","source":"Geometría releída del IFC; datum absoluto de proceso provisional","status":"derivado"},{"label":"Cota inferior de visualización","value":285.0,"unit":"m","source":"Geometría releída del IFC; datum absoluto de proceso provisional","status":"derivado"},{"label":"Cota superior de visualización","value":285.1,"unit":"m","source":"Geometría releída del IFC; datum absoluto de proceso provisional","status":"derivado"}]} | [] | {"Cota inferior relativa (m)":-1.1,"Cota superior relativa (m)":-1.0,"Cero absoluto de visualización (m)":286.1,"Estado del cero absoluto":"Provisional","Criterio":"Las cotas relativas proceden del dibujo; la equivalencia absoluta no está confirmada."} | SUP-C38 | [] | ["C38"] | ZD1 / DZ-1 | ["2CD0F","2CD5B","2CD27","2CDA3","2CD1F","2CD20","2CD7E","2CEC8","2CEA3"] | SUP-C38/Cimentación de soporte de tuberías C38 · capa de limpieza | {"boundingBoxM":{"min":[58.580456,40.401403,0.0],"max":[59.932718,41.753664,0.1]},"extentsM":[1.352262,1.352261,0.1],"meshSurfaceM2":3.36,"meshVolumeM3":0.144,"closedSolid":true,"basis":"Magnitudes de las mallas representadas, no cantidades certificadas de obra, compra o fabricación. Las partes pueden compartir superficies; no se suman como un despiece de materiales."} | {"profileId":"concrete_ha20","name":"Hormigón de limpieza HA-20","materialName":"Hormigón de limpieza HA-20","physicalMaterialStatus":"documentado","physicalMaterialSource":"Secciones del fabricante: capa de limpieza de 100 mm; nota 2CED5","appearanceStatus":"criterio_visual","appearanceBasis":"Interpretación visual del material documental; el acabado, tono y parámetros PBR no son una especificación contractual.","note":"La apariencia gráfica no modifica ni confirma la especificación física del material."} | {"elementId":"found_0904_d6d3f1360fbb4e","ifcGuid":"2h$R1LZ6XNIeEUkwjUKfkK","ifcClass":"IfcSlab","buildingId":"process_plant","buildingName":"Zona de separación de aire","sourceDocumentId":"LHD2609-JG00100-20260904","sourceRepresentationKind":"foundation"} | {"profileId":"concrete_ha20","name":"Hormigón de limpieza HA-20","status":"criterio_visual","basis":"Interpretación visual del material documental; el acabado, tono y parámetros PBR no son una especificación contractual.","physicalMaterialUnchanged":true} |  | 2CD0F, 2CD5B, 2CD27, 2CDA3, 2CD1F, 2CD20, 2CD7E, 2CEC8, 2CEA3 | Hormigón de limpieza HA-20 | -1.1 | -1 | 1.44 | 0.144 | Contornos y sección documentados por el fabricante | Hormigón de limpieza HA-20 | found_0904_d6d3f1360fbb4e | documentado | Secciones del fabricante: capa de limpieza de 100 mm; nota 2CED5 | 1.2 | 1.2 | concrete_ha20 | [0.721569,0.709804,0.658824] | 0.98
Cimentación de soporte de tuberías C39 · capa de limpieza | Hormigón de limpieza HA-20 | 1.35226 | 1.35226 | 0.1 | 285 | 285.1 | 3.36 | 0.144 | {"documentId":"LHD2609-JG00100-20260904","title":"Cimentaciones de equipos y pedestales del fabricante · revisión recibida 04/09/2026","date":"2026-09-04","sheet":"ZD1 / DZ-1","fileName":"LHD2609-JG00100_20260904.dwg","revisionCaveat":"Fecha de revisión tomada del nombre recibido; cajetines internos mantienen 02/07/2026 y algunos textos de plantilla.","sourceFileSha256":"b42eb027b7bc0b14c38d1d13514f4899b58a732aa8d0ba2ccf10fa2fc3192890"} | {"name":"Hormigón de limpieza HA-20","status":"documentado","source":"Secciones del fabricante: capa de limpieza de 100 mm; nota 2CED5"} | {"documented":[{"label":"Extensión local X","value":1.2,"unit":"m","source":"2CD10, 2CD5C, 2CD28, 2CDA4, 2CD1D, 2CD1E, 2CD7F, 2CEC9, 2CEA4","status":"derivada del contorno CAD"},{"label":"Extensión local Y","value":1.2,"unit":"m","source":"2CD10, 2CD5C, 2CD28, 2CDA4, 2CD1D, 2CD1E, 2CD7F, 2CEC9, 2CEA4","status":"derivada del contorno CAD"},{"label":"Cota inferior relativa adoptada","value":-1.1,"unit":"m","source":"ZD1 / DZ-1","status":"documentada"},{"label":"Cota superior relativa adoptada","value":-1.0,"unit":"m","source":"ZD1 / DZ-1","status":"documentada / separación por material"}],"geometry":[{"label":"Extensión de la malla en X","value":1.3522609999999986,"unit":"m","source":"Geometría releída del IFC; datum absoluto de proceso provisional","status":"derivado"},{"label":"Extensión de la malla en Y","value":1.3522620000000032,"unit":"m","source":"Geometría releída del IFC; datum absoluto de proceso provisional","status":"derivado"},{"label":"Extensión de la malla en Z","value":0.1,"unit":"m","source":"Geometría releída del IFC; datum absoluto de proceso provisional","status":"derivado"},{"label":"Cota inferior de visualización","value":285.0,"unit":"m","source":"Geometría releída del IFC; datum absoluto de proceso provisional","status":"derivado"},{"label":"Cota superior de visualización","value":285.1,"unit":"m","source":"Geometría releída del IFC; datum absoluto de proceso provisional","status":"derivado"}]} | [] | {"Cota inferior relativa (m)":-1.1,"Cota superior relativa (m)":-1.0,"Cero absoluto de visualización (m)":286.1,"Estado del cero absoluto":"Provisional","Criterio":"Las cotas relativas proceden del dibujo; la equivalencia absoluta no está confirmada."} | SUP-C39 | [] | ["C39"] | ZD1 / DZ-1 | ["2CD10","2CD5C","2CD28","2CDA4","2CD1D","2CD1E","2CD7F","2CEC9","2CEA4"] | SUP-C39/Cimentación de soporte de tuberías C39 · capa de limpieza | {"boundingBoxM":{"min":[60.165546,40.183476,0.0],"max":[61.517807,41.535738,0.1]},"extentsM":[1.352261,1.352262,0.1],"meshSurfaceM2":3.36,"meshVolumeM3":0.144,"closedSolid":true,"basis":"Magnitudes de las mallas representadas, no cantidades certificadas de obra, compra o fabricación. Las partes pueden compartir superficies; no se suman como un despiece de materiales."} | {"profileId":"concrete_ha20","name":"Hormigón de limpieza HA-20","materialName":"Hormigón de limpieza HA-20","physicalMaterialStatus":"documentado","physicalMaterialSource":"Secciones del fabricante: capa de limpieza de 100 mm; nota 2CED5","appearanceStatus":"criterio_visual","appearanceBasis":"Interpretación visual del material documental; el acabado, tono y parámetros PBR no son una especificación contractual.","note":"La apariencia gráfica no modifica ni confirma la especificación física del material."} | {"elementId":"found_0904_34081c29d5acca","ifcGuid":"3zjLduwqnMQP7oFmPSysJL","ifcClass":"IfcSlab","buildingId":"process_plant","buildingName":"Zona de separación de aire","sourceDocumentId":"LHD2609-JG00100-20260904","sourceRepresentationKind":"foundation"} | {"profileId":"concrete_ha20","name":"Hormigón de limpieza HA-20","status":"criterio_visual","basis":"Interpretación visual del material documental; el acabado, tono y parámetros PBR no son una especificación contractual.","physicalMaterialUnchanged":true} |  | 2CD10, 2CD5C, 2CD28, 2CDA4, 2CD1D, 2CD1E, 2CD7F, 2CEC9, 2CEA4 | Hormigón de limpieza HA-20 | -1.1 | -1 | 1.44 | 0.144 | Contornos y sección documentados por el fabricante | Hormigón de limpieza HA-20 | found_0904_34081c29d5acca | documentado | Secciones del fabricante: capa de limpieza de 100 mm; nota 2CED5 | 1.2 | 1.2 | concrete_ha20 | [0.721569,0.709804,0.658824] | 0.98
Cimentación de soporte de tuberías C40 · capa de limpieza | Hormigón de limpieza HA-20 | 1.35226 | 1.35226 | 0.1 | 285 | 285.1 | 3.36 | 0.144 | {"documentId":"LHD2609-JG00100-20260904","title":"Cimentaciones de equipos y pedestales del fabricante · revisión recibida 04/09/2026","date":"2026-09-04","sheet":"ZD1 / DZ-1","fileName":"LHD2609-JG00100_20260904.dwg","revisionCaveat":"Fecha de revisión tomada del nombre recibido; cajetines internos mantienen 02/07/2026 y algunos textos de plantilla.","sourceFileSha256":"b42eb027b7bc0b14c38d1d13514f4899b58a732aa8d0ba2ccf10fa2fc3192890"} | {"name":"Hormigón de limpieza HA-20","status":"documentado","source":"Secciones del fabricante: capa de limpieza de 100 mm; nota 2CED5"} | {"documented":[{"label":"Extensión local X","value":1.2,"unit":"m","source":"2CD11, 2CD5D, 2CD29, 2CDA5, 2CD1A, 2CD1B, 2CD80, 2CECA, 2CEA5","status":"derivada del contorno CAD"},{"label":"Extensión local Y","value":1.2,"unit":"m","source":"2CD11, 2CD5D, 2CD29, 2CDA5, 2CD1A, 2CD1B, 2CD80, 2CECA, 2CEA5","status":"derivada del contorno CAD"},{"label":"Cota inferior relativa adoptada","value":-1.1,"unit":"m","source":"ZD1 / DZ-1","status":"interpretación con conflicto conservado"},{"label":"Cota superior relativa adoptada","value":-1.0,"unit":"m","source":"ZD1 / DZ-1","status":"documentada / separación por material"}],"geometry":[{"label":"Extensión de la malla en X","value":1.3522610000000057,"unit":"m","source":"Geometría releída del IFC; datum absoluto de proceso provisional","status":"derivado"},{"label":"Extensión de la malla en Y","value":1.352261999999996,"unit":"m","source":"Geometría releída del IFC; datum absoluto de proceso provisional","status":"derivado"},{"label":"Extensión de la malla en Z","value":0.1,"unit":"m","source":"Geometría releída del IFC; datum absoluto de proceso provisional","status":"derivado"},{"label":"Cota inferior de visualización","value":285.0,"unit":"m","source":"Geometría releída del IFC; datum absoluto de proceso provisional","status":"derivado"},{"label":"Cota superior de visualización","value":285.1,"unit":"m","source":"Geometría releída del IFC; datum absoluto de proceso provisional","status":"derivado"}]} | ["Identificador original HA-40 en columna de posición; C40 se infiere por secuencia. Se conserva el original y no se interpreta como material."] | {"Cota inferior relativa (m)":-1.1,"Cota superior relativa (m)":-1.0,"Cero absoluto de visualización (m)":286.1,"Estado del cero absoluto":"Provisional","Criterio":"Las cotas relativas proceden del dibujo; la equivalencia absoluta no está confirmada."} | SUP-C40 | [] | ["C40"] | ZD1 / DZ-1 | ["2CD11","2CD5D","2CD29","2CDA5","2CD1A","2CD1B","2CD80","2CECA","2CEA5"] | SUP-C40/Cimentación de soporte de tuberías C40 · capa de limpieza | {"boundingBoxM":{"min":[58.171845,37.42936,0.0],"max":[59.524106,38.781622,0.1]},"extentsM":[1.352261,1.352262,0.1],"meshSurfaceM2":3.36,"meshVolumeM3":0.144,"closedSolid":true,"basis":"Magnitudes de las mallas representadas, no cantidades certificadas de obra, compra o fabricación. Las partes pueden compartir superficies; no se suman como un despiece de materiales."} | {"profileId":"concrete_ha20","name":"Hormigón de limpieza HA-20","materialName":"Hormigón de limpieza HA-20","physicalMaterialStatus":"documentado","physicalMaterialSource":"Secciones del fabricante: capa de limpieza de 100 mm; nota 2CED5","appearanceStatus":"criterio_visual","appearanceBasis":"Interpretación visual del material documental; el acabado, tono y parámetros PBR no son una especificación contractual.","note":"La apariencia gráfica no modifica ni confirma la especificación física del material."} | {"elementId":"found_0904_c5fead390dbced","ifcGuid":"1ikoz3lvnOtQA5MxO3bB4k","ifcClass":"IfcSlab","buildingId":"process_plant","buildingName":"Zona de separación de aire","sourceDocumentId":"LHD2609-JG00100-20260904","sourceRepresentationKind":"foundation"} | {"profileId":"concrete_ha20","name":"Hormigón de limpieza HA-20","status":"criterio_visual","basis":"Interpretación visual del material documental; el acabado, tono y parámetros PBR no son una especificación contractual.","physicalMaterialUnchanged":true} |  | 2CD11, 2CD5D, 2CD29, 2CDA5, 2CD1A, 2CD1B, 2CD80, 2CECA, 2CEA5 | Hormigón de limpieza HA-20 | -1.1 | -1 | 1.44 | 0.144 | Sección y contornos del fabricante; incidencias conservadas | Hormigón de limpieza HA-20 | found_0904_c5fead390dbced | documentado | Secciones del fabricante: capa de limpieza de 100 mm; nota 2CED5 | 1.2 | 1.2 | concrete_ha20 | [0.721569,0.709804,0.658824] | 0.98 | Identificador original HA-40 en columna de posición; C40 se infiere por secuencia. Se conserva el original y no se interpreta como material.
Cimentación de soporte de tuberías C41 · capa de limpieza | Hormigón de limpieza HA-20 | 1.35226 | 1.35226 | 0.1 | 285 | 285.1 | 3.36 | 0.144 | {"documentId":"LHD2609-JG00100-20260904","title":"Cimentaciones de equipos y pedestales del fabricante · revisión recibida 04/09/2026","date":"2026-09-04","sheet":"ZD1 / DZ-1","fileName":"LHD2609-JG00100_20260904.dwg","revisionCaveat":"Fecha de revisión tomada del nombre recibido; cajetines internos mantienen 02/07/2026 y algunos textos de plantilla.","sourceFileSha256":"b42eb027b7bc0b14c38d1d13514f4899b58a732aa8d0ba2ccf10fa2fc3192890"} | {"name":"Hormigón de limpieza HA-20","status":"documentado","source":"Secciones del fabricante: capa de limpieza de 100 mm; nota 2CED5"} | {"documented":[{"label":"Extensión local X","value":1.2,"unit":"m","source":"2CD2C, 2CD5E, 2CD2F, 2CDA6, 2CD2D, 2CD2E, 2CD81, 2CECB, 2CEA6","status":"derivada del contorno CAD"},{"label":"Extensión local Y","value":1.2,"unit":"m","source":"2CD2C, 2CD5E, 2CD2F, 2CDA6, 2CD2D, 2CD2E, 2CD81, 2CECB, 2CEA6","status":"derivada del contorno CAD"},{"label":"Cota inferior relativa adoptada","value":-1.1,"unit":"m","source":"ZD1 / DZ-1","status":"documentada"},{"label":"Cota superior relativa adoptada","value":-1.0,"unit":"m","source":"ZD1 / DZ-1","status":"documentada / separación por material"}],"geometry":[{"label":"Extensión de la malla en X","value":1.352261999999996,"unit":"m","source":"Geometría releída del IFC; datum absoluto de proceso provisional","status":"derivado"},{"label":"Extensión de la malla en Y","value":1.3522620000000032,"unit":"m","source":"Geometría releída del IFC; datum absoluto de proceso provisional","status":"derivado"},{"label":"Extensión de la malla en Z","value":0.1,"unit":"m","source":"Geometría releída del IFC; datum absoluto de proceso provisional","status":"derivado"},{"label":"Cota inferior de visualización","value":285.0,"unit":"m","source":"Geometría releída del IFC; datum absoluto de proceso provisional","status":"derivado"},{"label":"Cota superior de visualización","value":285.1,"unit":"m","source":"Geometría releída del IFC; datum absoluto de proceso provisional","status":"derivado"}]} | [] | {"Cota inferior relativa (m)":-1.1,"Cota superior relativa (m)":-1.0,"Cero absoluto de visualización (m)":286.1,"Estado del cero absoluto":"Provisional","Criterio":"Las cotas relativas proceden del dibujo; la equivalencia absoluta no está confirmada."} | SUP-C41 | [] | ["C41"] | ZD1 / DZ-1 | ["2CD2C","2CD5E","2CD2F","2CDA6","2CD2D","2CD2E","2CD81","2CECB","2CEA6"] | SUP-C41/Cimentación de soporte de tuberías C41 · capa de limpieza | {"boundingBoxM":{"min":[59.756934,37.211434,0.0],"max":[61.109196,38.563696,0.1]},"extentsM":[1.352262,1.352262,0.1],"meshSurfaceM2":3.36,"meshVolumeM3":0.144,"closedSolid":true,"basis":"Magnitudes de las mallas representadas, no cantidades certificadas de obra, compra o fabricación. Las partes pueden compartir superficies; no se suman como un despiece de materiales."} | {"profileId":"concrete_ha20","name":"Hormigón de limpieza HA-20","materialName":"Hormigón de limpieza HA-20","physicalMaterialStatus":"documentado","physicalMaterialSource":"Secciones del fabricante: capa de limpieza de 100 mm; nota 2CED5","appearanceStatus":"criterio_visual","appearanceBasis":"Interpretación visual del material documental; el acabado, tono y parámetros PBR no son una especificación contractual.","note":"La apariencia gráfica no modifica ni confirma la especificación física del material."} | {"elementId":"found_0904_6cd6d1c89f6557","ifcGuid":"1ozw9RTnHRsezE22vHxUeY","ifcClass":"IfcSlab","buildingId":"process_plant","buildingName":"Zona de separación de aire","sourceDocumentId":"LHD2609-JG00100-20260904","sourceRepresentationKind":"foundation"} | {"profileId":"concrete_ha20","name":"Hormigón de limpieza HA-20","status":"criterio_visual","basis":"Interpretación visual del material documental; el acabado, tono y parámetros PBR no son una especificación contractual.","physicalMaterialUnchanged":true} |  | 2CD2C, 2CD5E, 2CD2F, 2CDA6, 2CD2D, 2CD2E, 2CD81, 2CECB, 2CEA6 | Hormigón de limpieza HA-20 | -1.1 | -1 | 1.44 | 0.144 | Contornos y sección documentados por el fabricante | Hormigón de limpieza HA-20 | found_0904_6cd6d1c89f6557 | documentado | Secciones del fabricante: capa de limpieza de 100 mm; nota 2CED5 | 1.2 | 1.2 | concrete_ha20 | [0.721569,0.709804,0.658824] | 0.98

# IfcSlab: Pavimentos exteriores (2)
In: Parcela industrial Jinhong
Description: Pavimentos exteriores; PredefinedType: USERDEFINED; Document: Planos de urbanización y ordenación general de Jinhong; Group: Urbanización; BIM · Viales y pavimentos
JH_DimensionesDelModelo - Espesor de visualización adoptado: 0.1 m
JH_InformacionBIM - buildingId: site; buildingName: Urbanización y parcela; level: Exterior · rasantes de proyecto pendientes de coordinación; category: Pavimentos exteriores; ifcClass: IfcSlab; material: {"name":"No especificado","source":"Sin especificación de material en la documentación revisada","status":"unknown"}; source: {"documentId":"URB-20260731","title":"Planos de urbanización y ordenación general de Jinhong","sheet":"U004 · página 5","date":"2026-07-31"}; status: provisional; issues: ["Espesor supuesto exclusivamente para visualizar la superficie; material, composición y espesor constructivo sin especificar.","Cotas interpoladas a partir de puntos de proyecto del plano general. No sustituyen la rasante aprobada, los perfiles de viales ni el TIN de proyecto."]; ifcAssociations: {"material":false,"document":true,"quantities":true,"containerGuid":"17utmjd_LKsAVvPyuSUhFt","containerName":"Parcela industrial Jinhong"}; visualLayer: {"id":"roads","name":"Viales y pavimentos"}; materialAppearance: {"profileId":"exterior_concrete","name":"Pavimento exterior · hormigón provisional","materialName":"No especificado","physicalMaterialStatus":"unknown","physicalMaterialSource":"Sin especificación de material en la documentación revisada","appearanceStatus":"provisional","appearanceBasis":"Criterio visual autorizado para plataformas y pavimentos; material y sección constructiva pendientes.","note":"La apariencia gráfica no modifica ni confirma la especificación física del material."}; componentSeparation: {"status":"objeto_independiente","note":"Control de visibilidad del objeto completo; la clasificación no altera la malla."}; classification: {"layerId":"roads","layerName":"Viales y pavimentos","role":"Pavimentos exteriores","basis":"Clasificación por función del elemento; no modifica las especificaciones documentales."}; layerId: roads; appearance: {"profileId":"exterior_concrete","name":"Pavimento exterior · hormigón provisional","status":"provisional","basis":"Criterio visual autorizado para plataformas y pavimentos; material y sección constructiva pendientes.","physicalMaterialUnchanged":true}
JH_Trazabilidad - Documento de origen: Planos de urbanización y ordenación general de Jinhong · 2026-07-31 · U004 · página 5; Lámina de origen: U004 · página 5 del PDF; Geometría en planta: Triángulos de relleno originales del PDF, registrados mediante puntos de control UTM; contorno extraído de la documentación.; Estado de las cotas: Superficie de visualización obtenida por interpolación de las cotas de proyecto indicadas. No equivale a un perfil longitudinal aprobado ni al TIN original de proyecto.; Espesor de visualización (m): 0.1; Estado del espesor: Espesor supuesto exclusivamente para visualización; no utilizable en mediciones.; Estado del modelo: Coordinación preliminar; pendiente de revisión.; Disciplina: Urbanización; Clase IFC: IfcSlab; Fase del modelo: V0.1 · Reconstrucción a partir de planos y coordinación preliminar; Representación geométrica IFC: Sólido IFC4 mediante malla triangular cerrada; Aplicabilidad a mediciones: Los equipos se representan mediante envolventes. Los espesores y alturas supuestos y el volumen de las envolventes no representan cantidades de materiales, compras, construcción o fabricación.; Material: No especificado; Estado de la información: provisional; Capa BIM: Viales y pavimentos; Acabado de visualización: Pavimento exterior · hormigón provisional; Estado del acabado: provisional; Categoria: Pavimentos exteriores; ClaseIFC: IfcSlab; EstadoDeInformacion: provisional; DocumentoFuente: {"documentId":"URB-20260731","title":"Planos de urbanización y ordenación general de Jinhong","sheet":"U004 · página 5","date":"2026-07-31"}; IncidenciasPendientes: ["Espesor supuesto exclusivamente para visualizar la superficie; material, composición y espesor constructivo sin especificar.","Cotas interpoladas a partir de puntos de proyecto del plano general. No sustituyen la rasante aprobada, los perfiles de viales ni el TIN de proyecto."]; UsoDeLasMagnitudes: Geometría de coordinación. Los volúmenes de referencia y subcomponentes no son cantidades de material ni componentes de fabricación certificados.
JH_EvidenciaDeMaterial - name: No especificado; source: Sin especificación de material en la documentación revisada; status: unknown
JH_CapaBIM - IdentificadorCapa: roads; NombreCapa: Viales y pavimentos; Funcion: Pavimentos exteriores; VisibilidadInicial: yes
JH_AcabadoVisual - Perfil: exterior_concrete; Acabado: Pavimento exterior · hormigón provisional; ColorRGB: [0.698039,0.690196,0.647059]; Rugosidad: 0.94; Metallicidad: 0; Estado: provisional; Referencia: Criterio visual autorizado para plataformas y pavimentos; material y sección constructiva pendientes.; Nota: La apariencia no certifica el material físico ni el acabado de fabricación.
Name | Extensión de la malla en X (m) = ExtensionX (m) | Extensión de la malla en Y (m) = ExtensionY (m) | Extensión de la malla en Z (m) = ExtensionZ (m) | Cota inferior del modelo (m) | Cota superior del modelo (m) | Superficie proyectada en planta extraída del PDF (m2) = Superficie proyectada en planta (m²) | Reference = Identificador del objeto = Identificador | SuperficieDeLaMalla (m2) | VolumenGeometrico (m3) | dimensions | positioning = PosicionYEstado | geometryMetrics | visualizationIdentity
Zona pavimentada 01 | 16.1022 | 6.12241 | 0.443436 | 285.602 | 286.045 | 63.063 | site_004 | 130.1 | 6.30633 | {"documented":[],"geometry":[{"label":"Extensión de la malla en X","value":16.102207,"unit":"m","source":"Calculada a partir de los vértices del modelo","status":"derivado"},{"label":"Extensión de la malla en Y","value":6.12241,"unit":"m","source":"Calculada a partir de los vértices del modelo","status":"derivado"},{"label":"Extensión de la malla en Z","value":0.443436,"unit":"m","source":"Calculada a partir de los vértices del modelo","status":"derivado"},{"label":"Cota inferior del modelo","value":285.60182,"unit":"m","source":"Coordenada Z mínima de la malla más origen vertical de 285 m","status":"derivado"},{"label":"Cota superior del modelo","value":286.045256,"unit":"m","source":"Coordenada Z máxima de la malla más origen vertical de 285 m","status":"derivado"},{"label":"Superficie proyectada en planta extraída del PDF","value":63.063,"unit":"m²","source":"URB-20260731 · U004 · triangulación del relleno","status":"derivado"},{"label":"Espesor de visualización adoptado","value":0.1,"unit":"m","source":"Convención de visualización del modelo","status":"provisional"}],"notes":["Las extensiones de la malla se miden en los ejes del proyecto tras el giro de implantación; no sustituyen las dimensiones locales del fabricante.","La envolvente, su volumen y los espesores de visualización no son volúmenes de material ni cantidades de compra, construcción o fabricación.","Las dimensiones documentadas distinguen cotas explícitas y medidas extraídas de contornos CAD; las dimensiones geométricas describen únicamente la malla publicada."]} | {"horizontalStatus":"derivado","verticalStatus":"provisional","baseElevationM":285.60182,"note":"Superficie de visualización obtenida por interpolación de las cotas de proyecto indicadas. No equivale a un perfil longitudinal aprobado ni al TIN original de proyecto."} | {"boundingBoxM":{"min":[9.249072,32.740098,0.60182],"max":[25.351279,38.862508,1.045256]},"extentsM":[16.102207,6.12241,0.443436],"meshSurfaceM2":130.099516,"meshVolumeM3":6.306335,"closedSolid":true,"basis":"Geometría triangulada releída del IFC; envolventes y magnitudes no contractuales."} | {"elementId":"site_004","ifcGuid":"2ngwE2Qi5O9uKARL1Cbo1q","ifcClass":"IfcSlab","buildingId":"site","buildingName":"Urbanización y parcela","sourceDocumentId":"URB-20260731","sourceRepresentationKind":"documentary_mesh"}
Zona pavimentada 02 | 17.4629 | 19.1727 | 0.266253 | 285.485 | 285.751 | 246.558 | site_005 | 499.842 | 24.6558 | {"documented":[],"geometry":[{"label":"Extensión de la malla en X","value":17.462938,"unit":"m","source":"Calculada a partir de los vértices del modelo","status":"derivado"},{"label":"Extensión de la malla en Y","value":19.172681,"unit":"m","source":"Calculada a partir de los vértices del modelo","status":"derivado"},{"label":"Extensión de la malla en Z","value":0.266253,"unit":"m","source":"Calculada a partir de los vértices del modelo","status":"derivado"},{"label":"Cota inferior del modelo","value":285.484737,"unit":"m","source":"Coordenada Z mínima de la malla más origen vertical de 285 m","status":"derivado"},{"label":"Cota superior del modelo","value":285.75099,"unit":"m","source":"Coordenada Z máxima de la malla más origen vertical de 285 m","status":"derivado"},{"label":"Superficie proyectada en planta extraída del PDF","value":246.558,"unit":"m²","source":"URB-20260731 · U004 · triangulación del relleno","status":"derivado"},{"label":"Espesor de visualización adoptado","value":0.1,"unit":"m","source":"Convención de visualización del modelo","status":"provisional"}],"notes":["Las extensiones de la malla se miden en los ejes del proyecto tras el giro de implantación; no sustituyen las dimensiones locales del fabricante.","La envolvente, su volumen y los espesores de visualización no son volúmenes de material ni cantidades de compra, construcción o fabricación.","Las dimensiones documentadas distinguen cotas explícitas y medidas extraídas de contornos CAD; las dimensiones geométricas describen únicamente la malla publicada."]} | {"horizontalStatus":"derivado","verticalStatus":"provisional","baseElevationM":285.484737,"note":"Superficie de visualización obtenida por interpolación de las cotas de proyecto indicadas. No equivale a un perfil longitudinal aprobado ni al TIN original de proyecto."} | {"boundingBoxM":{"min":[-0.015032,78.967899,0.484737],"max":[17.447906,98.14058,0.75099]},"extentsM":[17.462938,19.172681,0.266253],"meshSurfaceM2":499.842015,"meshVolumeM3":24.655809,"closedSolid":true,"basis":"Geometría triangulada releída del IFC; envolventes y magnitudes no contractuales."} | {"elementId":"site_005","ifcGuid":"3rgfMd2anTfwShxmz0K8u1","ifcClass":"IfcSlab","buildingId":"site","buildingName":"Urbanización y parcela","sourceDocumentId":"URB-20260731","sourceRepresentationKind":"documentary_mesh"}

# IfcSlab: Viales, Vial interior 01
In: Parcela industrial Jinhong
Description: Viales; PredefinedType: USERDEFINED; Document: Planos de urbanización y ordenación general de Jinhong; Group: Urbanización; BIM · Viales y pavimentos
JH_DimensionesDelModelo - Extensión de la malla en X: 135.323 m; Extensión de la malla en Y: 102.988 m; Extensión de la malla en Z: 2.39432 m; Cota inferior del modelo: 285.564 m; Cota superior del modelo: 287.958 m; Superficie proyectada en planta extraída del PDF: 2472.68 m2; Espesor de visualización adoptado: 0.1 m
Pset_SlabCommon - Reference: site_000
JH_MagnitudesGeometricas - ExtensionX: 135.323 m; ExtensionY: 102.988 m; ExtensionZ: 2.39432 m; SuperficieDeLaMalla: 5020.81 m2; VolumenGeometrico: 247.268 m3
JH_InformacionBIM - buildingId: site; buildingName: Urbanización y parcela; level: Exterior · rasantes de proyecto pendientes de coordinación; category: Viales; ifcClass: IfcSlab; material: {"name":"No especificado","source":"Sin especificación de material en la documentación revisada","status":"unknown"}; dimensions: {"documented":[],"geometry":[{"label":"Extensión de la malla en X","value":135.322635,"unit":"m","source":"Calculada a partir de los vértices del modelo","status":"derivado"},{"label":"Extensión de la malla en Y","value":102.987769,"unit":"m","source":"Calculada a partir de los vértices del modelo","status":"derivado"},{"label":"Extensión de la malla en Z","value":2.394324,"unit":"m","source":"Calculada a partir de los vértices del modelo","status":"derivado"},{"label":"Cota inferior del modelo","value":285.563628,"unit":"m","source":"Coordenada Z mínima de la malla más origen vertical de 285 m","status":"derivado"},{"label":"Cota superior del modelo","value":287.957952,"unit":"m","source":"Coordenada Z máxima de la malla más origen vertical de 285 m","status":"derivado"},{"label":"Superficie proyectada en planta extraída del PDF","value":2472.683,"unit":"m²","source":"URB-20260731 · U004 · triangulación del relleno","status":"derivado"},{"label":"Espesor de visualización adoptado","value":0.1,"unit":"m","source":"Convención de visualización del modelo","status":"provisional"}],"notes":["Las extensiones de la malla se miden en los ejes del proyecto tras el giro de implantación; no sustituyen las dimensiones locales del fabricante.","La envolvente, su volumen y los espesores de visualización no son volúmenes de material ni cantidades de compra, construcción o fabricación.","Las dimensiones documentadas distinguen cotas explícitas y medidas extraídas de contornos CAD; las dimensiones geométricas describen únicamente la malla publicada."]}; source: {"documentId":"URB-20260731","title":"Planos de urbanización y ordenación general de Jinhong","sheet":"U004 · página 5","date":"2026-07-31"}; status: provisional; positioning: {"horizontalStatus":"derivado","verticalStatus":"provisional","baseElevationM":285.563628,"note":"Superficie de visualización obtenida por interpolación de las cotas de proyecto indicadas. No equivale a un perfil longitudinal aprobado ni al TIN original de proyecto."}; issues: ["Espesor supuesto exclusivamente para visualizar la superficie; material, composición y espesor constructivo sin especificar.","Cotas interpoladas a partir de puntos de proyecto del plano general. No sustituyen la rasante aprobada, los perfiles de viales ni el TIN de proyecto."]; geometryMetrics: {"boundingBoxM":{"min":[-0.323346,5.043701,0.563628],"max":[134.999289,108.03147,2.957952]},"extentsM":[135.322635,102.987769,2.394324],"meshSurfaceM2":5020.807084,"meshVolumeM3":247.268305,"closedSolid":true,"basis":"Geometría triangulada releída del IFC; envolventes y magnitudes no contractuales."}; ifcAssociations: {"material":false,"document":true,"quantities":true,"containerGuid":"17utmjd_LKsAVvPyuSUhFt","containerName":"Parcela industrial Jinhong"}; visualLayer: {"id":"roads","name":"Viales y pavimentos"}; materialAppearance: {"profileId":"asphalt","name":"Vial · acabado asfáltico provisional","materialName":"No especificado","physicalMaterialStatus":"unknown","physicalMaterialSource":"Sin especificación de material en la documentación revisada","appearanceStatus":"provisional","appearanceBasis":"Criterio visual autorizado para urbanización; no confirma la composición ni el espesor constructivo del vial.","note":"La apariencia gráfica no modifica ni confirma la especificación física del material."}; componentSeparation: {"status":"objeto_independiente","note":"Control de visibilidad del objeto completo; la clasificación no altera la malla."}; visualizationIdentity: {"elementId":"site_000","ifcGuid":"1NGWJIhevJlRQjyiq9uJRj","ifcClass":"IfcSlab","buildingId":"site","buildingName":"Urbanización y parcela","sourceDocumentId":"URB-20260731","sourceRepresentationKind":"documentary_mesh"}; classification: {"layerId":"roads","layerName":"Viales y pavimentos","role":"Viales","basis":"Clasificación por función del elemento; no modifica las especificaciones documentales."}; layerId: roads; appearance: {"profileId":"asphalt","name":"Vial · acabado asfáltico provisional","status":"provisional","basis":"Criterio visual autorizado para urbanización; no confirma la composición ni el espesor constructivo del vial.","physicalMaterialUnchanged":true}
JH_Trazabilidad - Documento de origen: Planos de urbanización y ordenación general de Jinhong · 2026-07-31 · U004 · página 5; Lámina de origen: U004 · página 5 del PDF; Geometría en planta: Triángulos de relleno originales del PDF, registrados mediante puntos de control UTM; contorno extraído de la documentación.; Superficie proyectada en planta (m²): 2472.68; Estado de las cotas: Superficie de visualización obtenida por interpolación de las cotas de proyecto indicadas. No equivale a un perfil longitudinal aprobado ni al TIN original de proyecto.; Espesor de visualización (m): 0.1; Estado del espesor: Espesor supuesto exclusivamente para visualización; no utilizable en mediciones.; Estado del modelo: Coordinación preliminar; pendiente de revisión.; Identificador del objeto: site_000; Disciplina: Urbanización; Clase IFC: IfcSlab; Fase del modelo: V0.1 · Reconstrucción a partir de planos y coordinación preliminar; Representación geométrica IFC: Sólido IFC4 mediante malla triangular cerrada; Aplicabilidad a mediciones: Los equipos se representan mediante envolventes. Los espesores y alturas supuestos y el volumen de las envolventes no representan cantidades de materiales, compras, construcción o fabricación.; Material: No especificado; Estado de la información: provisional; Capa BIM: Viales y pavimentos; Acabado de visualización: Vial · acabado asfáltico provisional; Estado del acabado: provisional; Identificador: site_000; Categoria: Viales; ClaseIFC: IfcSlab; EstadoDeInformacion: provisional; DocumentoFuente: {"documentId":"URB-20260731","title":"Planos de urbanización y ordenación general de Jinhong","sheet":"U004 · página 5","date":"2026-07-31"}; IncidenciasPendientes: ["Espesor supuesto exclusivamente para visualizar la superficie; material, composición y espesor constructivo sin especificar.","Cotas interpoladas a partir de puntos de proyecto del plano general. No sustituyen la rasante aprobada, los perfiles de viales ni el TIN de proyecto."]; UsoDeLasMagnitudes: Geometría de coordinación. Los volúmenes de referencia y subcomponentes no son cantidades de material ni componentes de fabricación certificados.
JH_CriterioDePosicion - PosicionYEstado: {"horizontalStatus":"derivado","verticalStatus":"provisional","baseElevationM":285.563628,"note":"Superficie de visualización obtenida por interpolación de las cotas de proyecto indicadas. No equivale a un perfil longitudinal aprobado ni al TIN original de proyecto."}
JH_EvidenciaDeMaterial - name: No especificado; source: Sin especificación de material en la documentación revisada; status: unknown
JH_CapaBIM - IdentificadorCapa: roads; NombreCapa: Viales y pavimentos; Funcion: Viales; VisibilidadInicial: yes
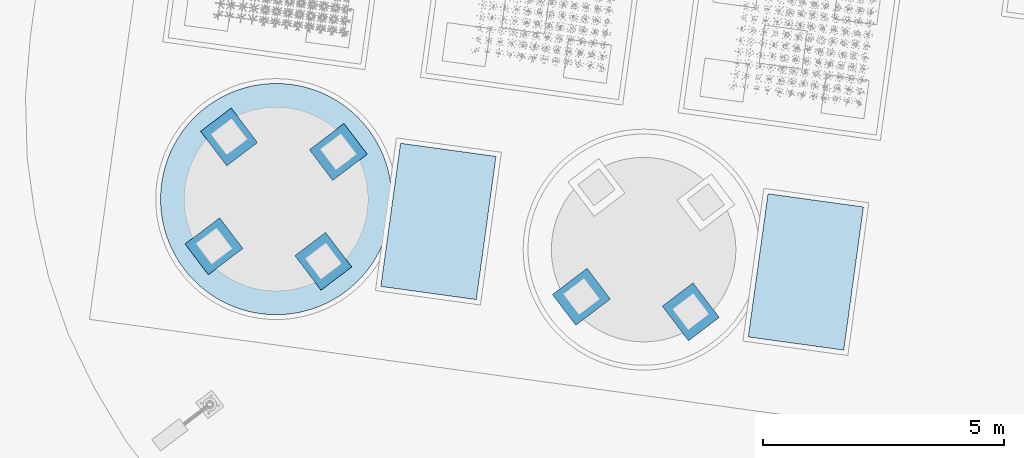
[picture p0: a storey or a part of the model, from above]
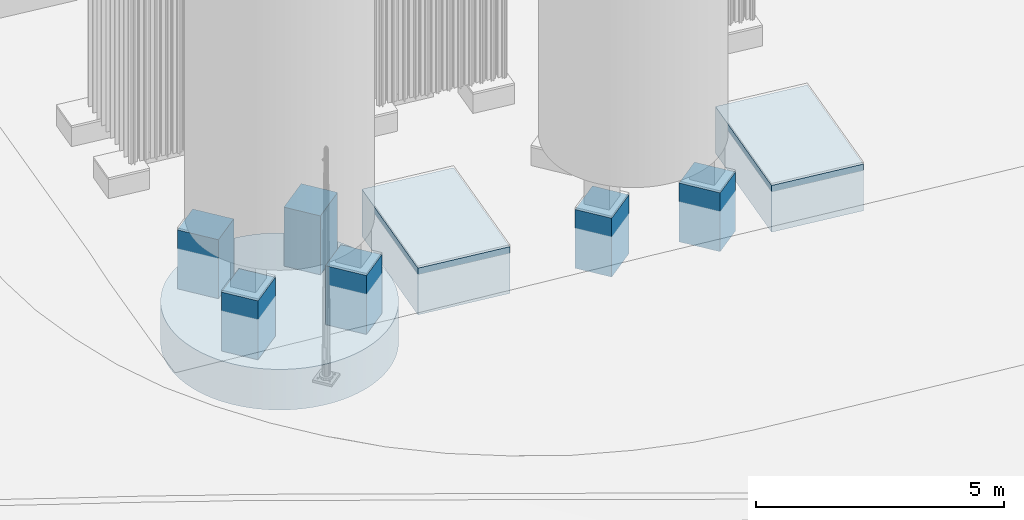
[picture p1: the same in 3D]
Properties of the parts of a building model (IFC4), part 111 of 134

# IfcSlab: Viales, Vial interior 01
JH_AcabadoVisual - Perfil: asphalt; Acabado: Vial · acabado asfáltico provisional; ColorRGB: [0.317647,0.345098,0.356863]; Rugosidad: 0.98; Metallicidad: 0; Estado: provisional; Referencia: Criterio visual autorizado para urbanización; no confirma la composición ni el espesor constructivo del vial.; Nota: La apariencia no certifica el material físico ni el acabado de fabricación.

# IfcStairFlight: Cimentación industrial (4)
In: Parcela industrial Jinhong
Description: Cimentación industrial; PredefinedType: USERDEFINED; Document: Cimentaciones de equipos y pedestales del fabricante · revisión recibida 04/09/2026; Group: Zona de separación de aire; BIM · Cimentaciones
JH_DimensionesDelModelo - Extensión de la malla en Z: 1.63139 m; Cota inferior de visualización: 285.969 m; Cota superior de visualización: 287.6 m
JH_MagnitudesGeometricas - ExtensionZ: 1.63139 m; SuperficieDeLaMalla: 9.07259 m2; VolumenGeometrico: 0.621024 m3
JH_InformacionBIM - material: {"name":"Hormigón armado · clase pendiente de confirmar","status":"Clase no confirmada en la hoja de equipo","source":"Geometría de cimentación del fabricante; no se extrapola HA-30 de la nota de pedestales."}; status: provisional; issues: ["La planta general y algunos croquis de apoyo muestran dimensiones transversales distintas. Se usan el contorno de cimentación y los centros de pilares de la implantación general; sección de viga VC1 400 × 400 mm y vuelo a 1050 mm del eje según detalle.","La capa de mortero sobre la losa no tiene una referencia vertical inequívoca; no se duplica una capa independiente en esa losa."]; positioning: {"Cota inferior relativa (m)":-0.13139135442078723,"Cota superior relativa (m)":1.5,"Cero absoluto de visualización (m)":286.1,"Estado del cero absoluto":"Provisional","Criterio":"Las cotas relativas proceden del dibujo; la equivalencia absoluta no está confirmada."}; supportPositionIds: []; buildingId: process_plant; buildingName: Zona de separación de aire; category: Cimentación industrial; representationKind: foundation; geometryStatus: Geometría de fabricante; implantación absoluta provisional; ifcClass: IfcStairFlight; visualLayer: {"id":"foundations","name":"Cimentaciones"}; materialAppearance: {"profileId":"concrete_reinforced","name":"Hormigón armado · gris natural","materialName":"Hormigón armado · clase pendiente de confirmar","physicalMaterialStatus":"Clase no confirmada en la hoja de equipo","physicalMaterialSource":"Geometría de cimentación del fabricante; no se extrapola HA-30 de la nota de pedestales.","appearanceStatus":"criterio_visual","appearanceBasis":"Interpretación visual del material documental; el acabado, tono y parámetros PBR no son una especificación contractual.","note":"La apariencia gráfica no modifica ni confirma la especificación física del material."}; componentSeparation: {"status":"objeto_independiente","note":"Control de visibilidad del objeto completo; la clasificación no altera la malla."}; classification: {"layerId":"foundations","layerName":"Cimentaciones","role":"Cimentación industrial","basis":"Clasificación por función del elemento; no modifica las especificaciones documentales."}; layerId: foundations; appearance: {"profileId":"concrete_reinforced","name":"Hormigón armado · gris natural","status":"criterio_visual","basis":"Interpretación visual del material documental; el acabado, tono y parámetros PBR no son una especificación contractual.","physicalMaterialUnchanged":true}
JH_Trazabilidad - Documento de origen: Cimentaciones de equipos y pedestales del fabricante · revisión recibida 04/09/2026; Material: Hormigón armado · clase pendiente de confirmar; Cota inferior relativa (m): -0.131391; Cota superior relativa (m): 1.5; Espesor o altura real de sección (m): 1.63139; Área de planta (m²): 2.79; Volumen geométrico (m³): 0.621024; Referencia vertical: Cotas relativas del dibujo. La equivalencia con un datum absoluto está pendiente.; Implantación para visualización: Z del modelo = cota relativa + 1,10 m. Correspondencia provisional con 286,10 m; no es cota de obra confirmada.; Estado de la geometría: Sección y contornos del fabricante; incidencias conservadas; Incidencias de origen: La planta general y algunos croquis de apoyo muestran dimensiones transversales distintas. Se usan el contorno de cimentación y los centros de pilares de la implantación general; sección de viga VC1 400 × 400 mm y vuelo a 1050 mm del eje según detalle. | La capa de mortero sobre la losa no tiene una referencia vertical inequívoca; no se duplica una capa independiente en esa losa.; Geometría de escalera: 8 × 187,5 mm; 7 huellas de220 mm; meseta de1250 mm; anchura1000 mm; garganta100 mm.; Posición de escalera: En el extremo con sobrelongitud de la base, conforme al esquema de cada plataforma.; Capa BIM: Cimentaciones; Acabado de visualización: Hormigón armado · gris natural; Estado del acabado: criterio_visual; Categoria: Cimentación industrial; ClaseIFC: IfcStairFlight; EstadoDeInformacion: provisional; IncidenciasPendientes: ["La planta general y algunos croquis de apoyo muestran dimensiones transversales distintas. Se usan el contorno de cimentación y los centros de pilares de la implantación general; sección de viga VC1 400 × 400 mm y vuelo a 1050 mm del eje según detalle.","La capa de mortero sobre la losa no tiene una referencia vertical inequívoca; no se duplica una capa independiente en esa losa."]; UsoDeLasMagnitudes: Geometría de coordinación. Los volúmenes de referencia y subcomponentes no son cantidades de material ni componentes de fabricación certificados.
JH_CriterioDePosicion - PosicionYEstado: {"Cota inferior relativa (m)":-0.13139135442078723,"Cota superior relativa (m)":1.5,"Cero absoluto de visualización (m)":286.1,"Estado del cero absoluto":"Provisional","Criterio":"Las cotas relativas proceden del dibujo; la equivalencia absoluta no está confirmada."}
JH_EvidenciaDeMaterial - name: Hormigón armado · clase pendiente de confirmar; status: Clase no confirmada en la hoja de equipo; source: Geometría de cimentación del fabricante; no se extrapola HA-30 de la nota de pedestales.
JH_DimensionesDocumentadas - Altura entre niveles: 1.5 m; Anchura de tramo: 1 m; Huella: 0.22 m; Contrahuella: 0.1875 m; Meseta: 1.25 m
JH_CapaBIM - IdentificadorCapa: foundations; NombreCapa: Cimentaciones; Funcion: Cimentación industrial; VisibilidadInicial: yes
JH_AcabadoVisual - Perfil: concrete_reinforced; Acabado: Hormigón armado · gris natural; ColorRGB: [0.666667,0.662745,0.619608]; Rugosidad: 0.96; Metallicidad: 0; Estado: criterio_visual; Referencia: Interpretación visual del material documental; el acabado, tono y parámetros PBR no son una especificación contractual.; Nota: La apariencia no certifica el material físico ni el acabado de fabricación.
Name | Extensión de la malla en X (m) = ExtensionX (m) | Extensión de la malla en Y (m) = ExtensionY (m) | source = DocumentoFuente | dimensions | assemblyId = Conjunto de cimentación | equipmentIds | sectionRef = Sección de referencia | sourceCadHandles | stableElementKey | geometryMetrics | visualizationIdentity | Equipos asociados | Identificadores CAD de referencia | Identificador
Cimentación y plataforma del módulo LV-CONTAINER · escalera de acceso · 8 contrahuellas | 2.9002 | 1.37069 | {"documentId":"LHD2609-JG00100-20260904","title":"Cimentaciones de equipos y pedestales del fabricante · revisión recibida 04/09/2026","date":"2026-09-04","sheet":"13–13","fileName":"LHD2609-JG00100_20260904.dwg","revisionCaveat":"Fecha de revisión tomada del nombre recibido; cajetines internos mantienen 02/07/2026 y algunos textos de plantilla.","sourceFileSha256":"b42eb027b7bc0b14c38d1d13514f4899b58a732aa8d0ba2ccf10fa2fc3192890"} | {"documented":[{"label":"Altura entre niveles","value":1.5,"unit":"m","source":"Detalle de escalera 13–13","status":"documentada"},{"label":"Anchura de tramo","value":1,"unit":"m","source":"Planta de plataforma 13–13","status":"documentada"},{"label":"Huella","value":0.22,"unit":"m","source":"Detalle de escalera","status":"documentada"},{"label":"Contrahuella","value":0.1875,"unit":"m","source":"Detalle de escalera","status":"documentada"},{"label":"Meseta","value":1.25,"unit":"m","source":"Detalle de escalera","status":"documentada"}],"geometry":[{"label":"Extensión de la malla en X","value":2.9002029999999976,"unit":"m","source":"Geometría releída del IFC; datum absoluto de proceso provisional","status":"derivado"},{"label":"Extensión de la malla en Y","value":1.3706900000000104,"unit":"m","source":"Geometría releída del IFC; datum absoluto de proceso provisional","status":"derivado"},{"label":"Extensión de la malla en Z","value":1.631391,"unit":"m","source":"Geometría releída del IFC; datum absoluto de proceso provisional","status":"derivado"},{"label":"Cota inferior de visualización","value":285.968609,"unit":"m","source":"Geometría releída del IFC; datum absoluto de proceso provisional","status":"derivado"},{"label":"Cota superior de visualización","value":287.6,"unit":"m","source":"Geometría releída del IFC; datum absoluto de proceso provisional","status":"derivado"}]} | F-LV-CONTAINER | ["LV-CONTAINER"] | 13–13 | ["55EB/55F1","1DB82","1DE55"] | F-LV-CONTAINER/Cimentación y plataforma del módulo LV-CONTAINER · escalera de acceso · 8 contrahuellas | {"boundingBoxM":{"min":[39.869011,82.679425,0.968609],"max":[42.769214,84.050115,2.6]},"extentsM":[2.900203,1.37069,1.631391],"meshSurfaceM2":9.072589,"meshVolumeM3":0.621024,"closedSolid":true,"basis":"Magnitudes de las mallas representadas, no cantidades certificadas de obra, compra o fabricación. Las partes pueden compartir superficies; no se suman como un despiece de materiales."} | {"elementId":"found_0904_0b74fa43408488","ifcGuid":"2YGgA48DnSCv52alJMKP7m","ifcClass":"IfcStairFlight","buildingId":"process_plant","buildingName":"Zona de separación de aire","sourceDocumentId":"LHD2609-JG00100-20260904","sourceRepresentationKind":"foundation"} | LV-CONTAINER | 55EB/55F1, 1DB82, 1DE55 | found_0904_0b74fa43408488
Cimentación y plataforma del módulo HV-CONTAINER · escalera de acceso · 8 contrahuellas | 1.37069 | 2.9002 | {"documentId":"LHD2609-JG00100-20260904","title":"Cimentaciones de equipos y pedestales del fabricante · revisión recibida 04/09/2026","date":"2026-09-04","sheet":"14–14","fileName":"LHD2609-JG00100_20260904.dwg","revisionCaveat":"Fecha de revisión tomada del nombre recibido; cajetines internos mantienen 02/07/2026 y algunos textos de plantilla.","sourceFileSha256":"b42eb027b7bc0b14c38d1d13514f4899b58a732aa8d0ba2ccf10fa2fc3192890"} | {"documented":[{"label":"Altura entre niveles","value":1.5,"unit":"m","source":"Detalle de escalera 14–14","status":"documentada"},{"label":"Anchura de tramo","value":1,"unit":"m","source":"Planta de plataforma 14–14","status":"documentada"},{"label":"Huella","value":0.22,"unit":"m","source":"Detalle de escalera","status":"documentada"},{"label":"Contrahuella","value":0.1875,"unit":"m","source":"Detalle de escalera","status":"documentada"},{"label":"Meseta","value":1.25,"unit":"m","source":"Detalle de escalera","status":"documentada"}],"geometry":[{"label":"Extensión de la malla en X","value":1.3706899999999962,"unit":"m","source":"Geometría releída del IFC; datum absoluto de proceso provisional","status":"derivado"},{"label":"Extensión de la malla en Y","value":2.9002040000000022,"unit":"m","source":"Geometría releída del IFC; datum absoluto de proceso provisional","status":"derivado"},{"label":"Extensión de la malla en Z","value":1.631391,"unit":"m","source":"Geometría releída del IFC; datum absoluto de proceso provisional","status":"derivado"},{"label":"Cota inferior de visualización","value":285.968609,"unit":"m","source":"Geometría releída del IFC; datum absoluto de proceso provisional","status":"derivado"},{"label":"Cota superior de visualización","value":287.6,"unit":"m","source":"Geometría releída del IFC; datum absoluto de proceso provisional","status":"derivado"}]} | F-HV-CONTAINER | ["HV-CONTAINER"] | 14–14 | ["553E/5544","1DB82","1DE55"] | F-HV-CONTAINER/Cimentación y plataforma del módulo HV-CONTAINER · escalera de acceso · 8 contrahuellas | {"boundingBoxM":{"min":[65.508255,79.988717,0.968609],"max":[66.878945,82.888921,2.6]},"extentsM":[1.37069,2.900204,1.631391],"meshSurfaceM2":9.072592,"meshVolumeM3":0.621024,"closedSolid":true,"basis":"Magnitudes de las mallas representadas, no cantidades certificadas de obra, compra o fabricación. Las partes pueden compartir superficies; no se suman como un despiece de materiales."} | {"elementId":"found_0904_ed5f59783c550d","ifcGuid":"1oBzQL10nUkB1JZHc4u8vp","ifcClass":"IfcStairFlight","buildingId":"process_plant","buildingName":"Zona de separación de aire","sourceDocumentId":"LHD2609-JG00100-20260904","sourceRepresentationKind":"foundation"} | HV-CONTAINER | 553E/5544, 1DB82, 1DE55 | found_0904_ed5f59783c550d
Cimentación y plataforma del módulo IC-CONTAINER · escalera de acceso · 8 contrahuellas | 2.9002 | 1.37069 | {"documentId":"LHD2609-JG00100-20260904","title":"Cimentaciones de equipos y pedestales del fabricante · revisión recibida 04/09/2026","date":"2026-09-04","sheet":"15–15","fileName":"LHD2609-JG00100_20260904.dwg","revisionCaveat":"Fecha de revisión tomada del nombre recibido; cajetines internos mantienen 02/07/2026 y algunos textos de plantilla.","sourceFileSha256":"b42eb027b7bc0b14c38d1d13514f4899b58a732aa8d0ba2ccf10fa2fc3192890"} | {"documented":[{"label":"Altura entre niveles","value":1.5,"unit":"m","source":"Detalle de escalera 15–15","status":"documentada"},{"label":"Anchura de tramo","value":1,"unit":"m","source":"Planta de plataforma 15–15","status":"documentada"},{"label":"Huella","value":0.22,"unit":"m","source":"Detalle de escalera","status":"documentada"},{"label":"Contrahuella","value":0.1875,"unit":"m","source":"Detalle de escalera","status":"documentada"},{"label":"Meseta","value":1.25,"unit":"m","source":"Detalle de escalera","status":"documentada"}],"geometry":[{"label":"Extensión de la malla en X","value":2.9002029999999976,"unit":"m","source":"Geometría releída del IFC; datum absoluto de proceso provisional","status":"derivado"},{"label":"Extensión de la malla en Y","value":1.3706890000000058,"unit":"m","source":"Geometría releída del IFC; datum absoluto de proceso provisional","status":"derivado"},{"label":"Extensión de la malla en Z","value":1.631391,"unit":"m","source":"Geometría releída del IFC; datum absoluto de proceso provisional","status":"derivado"},{"label":"Cota inferior de visualización","value":285.968609,"unit":"m","source":"Geometría releída del IFC; datum absoluto de proceso provisional","status":"derivado"},{"label":"Cota superior de visualización","value":287.6,"unit":"m","source":"Geometría releída del IFC; datum absoluto de proceso provisional","status":"derivado"}]} | F-IC-CONTAINER | ["IC-CONTAINER"] | 15–15 | ["5645/5652","1DB82","1DE55"] | F-IC-CONTAINER/Cimentación y plataforma del módulo IC-CONTAINER · escalera de acceso · 8 contrahuellas | {"boundingBoxM":{"min":[36.753346,60.017602,0.968609],"max":[39.653549,61.388291,2.6]},"extentsM":[2.900203,1.370689,1.631391],"meshSurfaceM2":9.072586,"meshVolumeM3":0.621024,"closedSolid":true,"basis":"Magnitudes de las mallas representadas, no cantidades certificadas de obra, compra o fabricación. Las partes pueden compartir superficies; no se suman como un despiece de materiales."} | {"elementId":"found_0904_ea78e8246d70ca","ifcGuid":"3qCkpML3DTyO9gDAr4e7Kv","ifcClass":"IfcStairFlight","buildingId":"process_plant","buildingName":"Zona de separación de aire","sourceDocumentId":"LHD2609-JG00100-20260904","sourceRepresentationKind":"foundation"} | IC-CONTAINER | 5645/5652, 1DB82, 1DE55 | found_0904_ea78e8246d70ca
Cimentación y plataforma del módulo MV-CONTAINER · escalera de acceso · 8 contrahuellas | 1.37069 | 2.9002 | {"documentId":"LHD2609-JG00100-20260904","title":"Cimentaciones de equipos y pedestales del fabricante · revisión recibida 04/09/2026","date":"2026-09-04","sheet":"16–16","fileName":"LHD2609-JG00100_20260904.dwg","revisionCaveat":"Fecha de revisión tomada del nombre recibido; cajetines internos mantienen 02/07/2026 y algunos textos de plantilla.","sourceFileSha256":"b42eb027b7bc0b14c38d1d13514f4899b58a732aa8d0ba2ccf10fa2fc3192890"} | {"documented":[{"label":"Altura entre niveles","value":1.5,"unit":"m","source":"Detalle de escalera 16–16","status":"documentada"},{"label":"Anchura de tramo","value":1,"unit":"m","source":"Planta de plataforma 16–16","status":"documentada"},{"label":"Huella","value":0.22,"unit":"m","source":"Detalle de escalera","status":"documentada"},{"label":"Contrahuella","value":0.1875,"unit":"m","source":"Detalle de escalera","status":"documentada"},{"label":"Meseta","value":1.25,"unit":"m","source":"Detalle de escalera","status":"documentada"}],"geometry":[{"label":"Extensión de la malla en X","value":1.3706900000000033,"unit":"m","source":"Geometría releída del IFC; datum absoluto de proceso provisional","status":"derivado"},{"label":"Extensión de la malla en Y","value":2.9002029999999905,"unit":"m","source":"Geometría releída del IFC; datum absoluto de proceso provisional","status":"derivado"},{"label":"Extensión de la malla en Z","value":1.631391,"unit":"m","source":"Geometría releída del IFC; datum absoluto de proceso provisional","status":"derivado"},{"label":"Cota inferior de visualización","value":285.968609,"unit":"m","source":"Geometría releída del IFC; datum absoluto de proceso provisional","status":"derivado"},{"label":"Cota superior de visualización","value":287.6,"unit":"m","source":"Geometría releída del IFC; datum absoluto de proceso provisional","status":"derivado"}]} | F-MV-CONTAINER | ["MV-CONTAINER"] | 16–16 | ["5599/559F","1DB82","1DE55"] | F-MV-CONTAINER/Cimentación y plataforma del módulo MV-CONTAINER · escalera de acceso · 8 contrahuellas | {"boundingBoxM":{"min":[45.248337,82.774156,0.968609],"max":[46.619027,85.674359,2.6]},"extentsM":[1.37069,2.900203,1.631391],"meshSurfaceM2":9.07259,"meshVolumeM3":0.621024,"closedSolid":true,"basis":"Magnitudes de las mallas representadas, no cantidades certificadas de obra, compra o fabricación. Las partes pueden compartir superficies; no se suman como un despiece de materiales."} | {"elementId":"found_0904_0c93b645a183af","ifcGuid":"25nfeZWkjIyQQETNnFRe15","ifcClass":"IfcStairFlight","buildingId":"process_plant","buildingName":"Zona de separación de aire","sourceDocumentId":"LHD2609-JG00100-20260904","sourceRepresentationKind":"foundation"} | MV-CONTAINER | 5599/559F, 1DB82, 1DE55 | found_0904_0c93b645a183af

# IfcTank (3)
In: Parcela industrial Jinhong
PredefinedType: STORAGE
JH_InformacionBIM - ifcClass: IfcTank; material: {"name":"No especificado","source":"Sin especificación de material en la documentación revisada","status":"unknown"}; status: provisional; ifcAssociations: {"material":false,"document":true,"quantities":true,"containerGuid":"17utmjd_LKsAVvPyuSUhFt","containerName":"Parcela industrial Jinhong"}
JH_Trazabilidad - Clase IFC: IfcTank; Representación geométrica IFC: Sólido IFC4 mediante malla triangular cerrada; Material: No especificado; Estado de la información: provisional; ClaseIFC: IfcTank; EstadoDeInformacion: provisional; UsoDeLasMagnitudes: Geometría de coordinación. Los volúmenes de referencia y subcomponentes no son cantidades de material ni componentes de fabricación certificados.
JH_EvidenciaDeMaterial - name: No especificado; source: Sin especificación de material en la documentación revisada; status: unknown
JH_CapaBIM - VisibilidadInicial: yes
JH_AcabadoVisual - Nota: La apariencia no certifica el material físico ni el acabado de fabricación.
Name | Description = category = Categoria = Funcion | Document | Extensión de la malla en X (m) = Extensión de la malla en Y (m) = ExtensionX (m) = ExtensionY (m) | Extensión de la malla en Z (m) = ExtensionZ (m) | SuperficieDeLaMalla (m2) | VolumenGeometrico (m3) | buildingId | buildingName | level | dimensions | JH_InformacionBIM, source = DocumentoFuente | positioning = PosicionYEstado | JH_InformacionBIM, issues = IncidenciasPendientes | geometryMetrics | visualLayer | materialAppearance | componentSeparation | visualizationIdentity | classification | layerId = IdentificadorCapa | appearance | Documento de origen | Diámetro (m) | Altura (m) | Identificador del objeto = Identificador | Disciplina | Fase del modelo | Aplicabilidad a mediciones | Capa BIM = NombreCapa | Acabado de visualización = Acabado | Estado del acabado = Estado | Perfil | ColorRGB | Rugosidad | Metallicidad | Referencia | Group | ElementosDeCimentacion = foundationIds | Relacion | Cota inferior de visualización (m) | Cota superior de visualización (m) | detailGeometry | installationSource = Fuente del nivel de apoyo | representationKind | parentEquipmentId = Identificador del fabricante o del modelo = Identificador del elemento = Identificador del equipo padre | parentEquipmentName = Equipo padre | parentEquipmentIfcClass | parentEquipmentDimensions | parentEquipmentPositioning | parentEquipmentIssues | parentEquipmentDetail | componentRole = Rol del componente | assemblyBBox | assemblyGeometryMetrics | manufacturerDetailsPending | component | assembly | foundationRelationship | installationSourceScope | componentIds | childComponentIds | sourcePartIds | parentEquipmentProperties | mainComponentSelectionBasis | photoAppearanceReview | Referencia en el plano del fabricante | Documento CAD derivado | Capa CAD de referencia | Identificadores CAD del contorno (handles) | Identificador CAD de la cota de altura (handle) | Cota de altura del fabricante (traducción) | Origen de las dimensiones | Grado de definición | Alcance de la geometría | Origen de la posición | Hipótesis de modelado = Estado de la cota de instalación = Criterio de instalación | Observaciones | Masa propia indicada (kg) | Carga variable indicada por el fabricante (kg) | Dimensiones de la plataforma de equipos (m) | Implantación de la plataforma de equipos | Convención de coordenadas | Detalle geométrico = horizontalStatus | Incidencias del detalle | Extensión X del conjunto refinado en ejes del fabricante (m) = Extensión Y del conjunto refinado en ejes del fabricante (m) | Nivel relativo de apoyo documentado (m) | Componente | Capa de visualización | Estado del material | Perfil visual del material | Fuente del componente = JH_DetalleGeometrico, source | Criterio de partición | Criterio de las dimensiones | Relación con cimentaciones | Aplicabilidad de las mediciones | Referencia dimensional del conjunto | heightSource | revision | verticalRule | status | unconfirmedDimensions | JH_DetalleGeometrico, issues | material | quantityUse | partsAreBOM | sourceInsertHandle | partCount | sourcePartHandles | actualExtentManufacturerAxesM | sourcePartId | sourceHandles | Fotografias | FechaRevision
Depósito de agua contra incendios · altura provisional de 6 m | Depósito de protección contra incendios | Planos de urbanización y ordenación general de Jinhong | 6.5 | 6 | 188.732 | 198.779 | site | Urbanización y parcela | Exterior · depósito de agua contra incendios | {"documented":[{"label":"Diámetro exterior según el plano general","value":6.5,"unit":"m","source":"URB-20260731 · U004","status":"documentado"}],"geometry":[{"label":"Extensión de la malla en X","value":6.5,"unit":"m","source":"Calculada a partir de los vértices del modelo","status":"derivado"},{"label":"Extensión de la malla en Y","value":6.5,"unit":"m","source":"Calculada a partir de los vértices del modelo","status":"derivado"},{"label":"Extensión de la malla en Z","value":6.0,"unit":"m","source":"Calculada a partir de los vértices del modelo","status":"derivado"},{"label":"Cota inferior del modelo","value":286.1,"unit":"m","source":"Coordenada Z mínima de la malla más origen vertical de 285 m","status":"derivado"},{"label":"Cota superior del modelo","value":292.1,"unit":"m","source":"Coordenada Z máxima de la malla más origen vertical de 285 m","status":"derivado"},{"label":"Altura provisional de la envolvente","value":6,"unit":"m","source":"Hipótesis de visualización sin altura confirmada en el plano","status":"provisional"}],"notes":["Las extensiones de la malla se miden en los ejes del proyecto tras el giro de implantación; no sustituyen las dimensiones locales del fabricante.","La envolvente, su volumen y los espesores de visualización no son volúmenes de material ni cantidades de compra, construcción o fabricación.","Las dimensiones documentadas distinguen cotas explícitas y medidas extraídas de contornos CAD; las dimensiones geométricas describen únicamente la malla publicada."]} | {"documentId":"URB-20260731","title":"Planos de urbanización y ordenación general de Jinhong","sheet":"U004 · página 5","date":"2026-07-31"} | {"horizontalStatus":"derivado","verticalStatus":"provisional","baseElevationM":286.1,"note":"Cota de representación derivada del modelo; superficie real de apoyo pendiente de coordinación."} | ["Envolvente provisional de visualización; la altura no está confirmada en el plano de origen. No permite calcular la capacidad del depósito.","Plano general más reciente: diámetro exterior 6,50 m. Arquitectura: radio 3,35 m. Estructura: diámetro de cimentación 6,0 m. Corresponden a referencias que requieren coordinación entre disciplinas.","Cota de apoyo y montaje pendiente de coordinación; no se ha validado la base real del depósito."] | {"boundingBoxM":{"min":[1.25035,28.35764,1.1],"max":[7.75035,34.85764,7.1]},"extentsM":[6.5,6.5,6.0],"meshSurfaceM2":188.732484,"meshVolumeM3":198.778733,"closedSolid":true,"basis":"Geometría triangulada releída del IFC; envolventes y magnitudes no contractuales."} | {"id":"utilities","name":"Servicios auxiliares"} | {"profileId":"equipment_white_tank","name":"Depósito · blanco cálido provisional","materialName":"No especificado","physicalMaterialStatus":"unknown","physicalMaterialSource":"Sin especificación de material en la documentación revisada","appearanceStatus":"provisional","appearanceBasis":"Referencia visual de fotografías públicas de Jinhong Gas / fabricante. Apariencia provisional para coordinación; fotografías oficiales pueden orientar el color, pero no acreditan el material, el acabado ni el equipo concreto.","note":"La apariencia gráfica no modifica ni confirma la especificación física del material."} | {"status":"objeto_independiente","note":"Control de visibilidad del objeto completo; la clasificación no altera la malla."} | {"elementId":"site_007","ifcGuid":"3_OYUaeP9RWehuHmBl2rSR","ifcClass":"IfcTank","buildingId":"site","buildingName":"Urbanización y parcela","sourceDocumentId":"URB-20260731","sourceRepresentationKind":"documentary_mesh"} | {"layerId":"utilities","layerName":"Servicios auxiliares","role":"Depósito de protección contra incendios","basis":"Clasificación por función del elemento; no modifica las especificaciones documentales."} | utilities | {"profileId":"equipment_white_tank","name":"Depósito · blanco cálido provisional","status":"provisional","basis":"Referencia visual de fotografías públicas de Jinhong Gas / fabricante. Apariencia provisional para coordinación; fotografías oficiales pueden orientar el color, pero no acreditan el material, el acabado ni el equipo concreto.","physicalMaterialUnchanged":true} | Planos de urbanización y ordenación general de Jinhong · 2026-07-31 · U004 · página 5 | 6.5 | 6 | site_007 | Equipos | V0.1 · Reconstrucción a partir de planos y coordinación preliminar | Los equipos se representan mediante envolventes. Los espesores y alturas supuestos y el volumen de las envolventes no representan cantidades de materiales, compras, construcción o fabricación. | Servicios auxiliares | Depósito · blanco cálido provisional | provisional | equipment_white_tank | [0.88,0.89,0.88] | 0.4 | 0.2 | Referencia visual de fotografías públicas de Jinhong Gas / fabricante. Apariencia provisional para coordinación; fotografías oficiales pueden orientar el color, pero no acreditan el material, el acabado ni el equipo concreto. | Equipos; BIM · Servicios auxiliares | JH_DimensionesDelModelo - Cota inferior del modelo: 286.1 m; Cota superior del modelo: 292.1 m; Altura provisional de la envolvente: 6 m; JH_Trazabilidad - Lámina de origen: U004 · página 5 del PDF; Centro UTM (m): [729404.50035, 4301581.60764]; Estado de la altura: Envolvente provisional de visualización; la altura no está confirmada en el plano de origen. No permite calcular la capacidad del depósito.; Discrepancias dimensionales: Plano general más reciente: diámetro exterior 6,50 m. Arquitectura: radio 3,35 m. Estructura: diámetro de cimentación 6,0 m. Corresponden a referencias que requieren coordinación entre disciplinas.; Estado del modelo: Planta basada en documentación; altura provisional.; JH_DimensionesDocumentadas - Diámetro exterior según el plano general: 6.5 m
Depósito de nitrógeno líquido SV1801A · Envolvente cilíndrica del depósito | Componente de equipo · envolvente exterior | Plano del fabricante: cargas de equipos; Plano del fabricante: implantación de equipos · referencia E7; Cimentaciones de equipos y pedestales del fabricante · revisión recibida 04/09/2026; Fotografía de referencia aportada · 01; Fotografía de referencia aportada · 02; Fotografía de referencia aportada · 04; Fotografía de referencia aportada · 06 | 3.82794 | 21.427 | 280.684 | 246.557 | process_plant | Planta de proceso | Apoyo relativo +0.500 m; cero absoluto provisional | {"documented":[{"label":"Referencia dimensional del conjunto","value":"Plano general y dimensiones globales de SV1801A; no se asignan esas dimensiones globales a este componente.","unit":"","source":"EQ-CARGAS-20260825 · Espacio modelo","status":"referencia_del_conjunto"}],"geometry":[{"label":"Extensión de la malla en X","value":3.827938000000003,"unit":"m","source":"Geometría releída del IFC; datum absoluto de proceso provisional","status":"derivado"},{"label":"Extensión de la malla en Y","value":3.827936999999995,"unit":"m","source":"Geometría releída del IFC; datum absoluto de proceso provisional","status":"derivado"},{"label":"Extensión de la malla en Z","value":21.427,"unit":"m","source":"Geometría releída del IFC; datum absoluto de proceso provisional","status":"derivado"},{"label":"Cota inferior de visualización","value":287.2,"unit":"m","source":"Geometría releída del IFC; datum absoluto de proceso provisional","status":"derivado"},{"label":"Cota superior de visualización","value":308.627,"unit":"m","source":"Geometría releída del IFC; datum absoluto de proceso provisional","status":"derivado"}],"notes":["Las dimensiones del equipo completo se conservan en parentEquipmentDimensions.","Las extensiones en X/Y son de los ejes del modelo y no sustituyen cotas locales de fabricación.","No se infieren espesores de chapa, tolerancias ni dimensiones de piezas a partir de la partición."]} | {"documentId":"EQ-CARGAS-20260825","title":"Plano del fabricante: cargas de equipos","sheet":"Espacio modelo","date":"2026-08-25","componentSourceHandles":["42F","434"]} | {"Estado de la planta":"Derivado del CAD y del giro de implantación","Nivel relativo del apoyo (m)":0.5,"Estado del nivel relativo":"Documentado en el plano de cimentaciones","Cero absoluto de visualización (m)":286.1,"Estado del cero absoluto":"Provisional","Cota del apoyo de visualización (m)":286.6,"Desplazamiento aplicado a la malla (m)":0.5000000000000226,"Criterio":"Nivel de apoyo relativo documentado. Se adopta el cero de proceso a 286,10 m solo para visualización; la equivalencia absoluta no está confirmada. No se añade un espesor de montaje sin cota del fabricante.","horizontalStatus":"derivado_del_conjunto","verticalStatus":"derivado_del_conjunto","coordinateSystem":"model_local_m","parentEquipmentId":"SV1801A","transformApplied":false,"note":"Coordenadas copiadas exactamente del equipo coordinado; no se ha movido, girado, elevado ni reescalado este componente.","foundationRelationship":"El apoyo y las cotas de instalación se documentan para el conjunto padre. Esta submalla no acredita un anclaje directo.","meshMinimumAbsoluteElevationM":287.2,"assemblyPlacementField":"parentEquipmentPositioning"} | ["Componente separado de una reconstrucción documental del conjunto. Las alturas y detalles parciales conservan las limitaciones del fabricante registradas en parentEquipmentIssues.","Esta representación exterior no crea una chapa hueca ni añade componentes internos no documentados.","La pertenencia al conjunto no demuestra apoyo o anclaje directo a la cimentación."] | {"boundingBoxM":{"min":[34.463015,30.600052,2.2],"max":[38.290953,34.427989,23.627]},"extentsM":[3.827938,3.827937,21.427],"meshSurfaceM2":280.683653,"meshVolumeM3":246.55715,"closedSolid":true,"basis":"Geometría de coordinación. Los volúmenes de referencia y subcomponentes no son cantidades de material ni componentes de fabricación certificados."} | {"id":"equipment_enclosures","name":"Envolventes de equipos"} | {"profileId":"equipment_white_tank_photo","name":"Depósito de nitrógeno · blanco satinado de referencia","materialName":"No especificado","physicalMaterialStatus":"unknown","physicalMaterialSource":"Sin especificación de material en la documentación revisada","appearanceStatus":"referencia_fotografica_provisional","appearanceBasis":"Fotografías reales aportadas el 08/09/2026, sin fecha de toma ni emplazamiento verificados. Depósitos esbeltos blancos en las fotografías 01, 02, 04 y 06. Las bandas cambian entre instalaciones; no se trasladan colores de servicio, proporciones ni apoyos. Tono y parámetros de visualización orientativos; no especifican pintura, aleación ni dimensiones.","appearanceReferences":["jinhong-official-asu","xinrui-jinhong-vaporizers"],"note":"El perfil visual no confirma material, grado ni acabado del componente."} | {"status":"componente_independiente","note":"Objeto independiente seleccionable. Las caras se asignan una sola vez entre todos los componentes del conjunto.","parentEquipmentId":"SV1801A","isAssemblyIdentityCarrier":true} | {"elementId":"SV1801A","ifcGuid":"1EEV2pFbzMUQXwXeX6CZae","ifcClass":"IfcTank","buildingId":"process_plant","buildingName":"Planta de proceso","sourceDocumentId":"EQ-CARGAS-20260825","sourceRepresentationKind":"equipmentComponent"} | {"layerId":"equipment_enclosures","layerName":"Envolventes de equipos","role":"Componente de equipo · envolvente exterior","basis":"Clasificación por función del elemento; no modifica las especificaciones documentales."} | equipment_enclosures | {"profileId":"equipment_white_tank_photo","name":"Depósito de nitrógeno · blanco satinado de referencia","status":"referencia_fotografica_provisional","basis":"Fotografías reales aportadas el 08/09/2026, sin fecha de toma ni emplazamiento verificados. Depósitos esbeltos blancos en las fotografías 01, 02, 04 y 06. Las bandas cambian entre instalaciones; no se trasladan colores de servicio, proporciones ni apoyos. Tono y parámetros de visualización orientativos; no especifican pintura, aleación ni dimensiones.","physicalMaterialUnchanged":true} | Plano del fabricante: cargas de equipos · 2026-08-25 · Espacio modelo; número de plano no identificado | 3.828 | 22.027 | SV1801A | Envolventes de equipos | Revisión de la zona de separación de aire · septiembre de 2026 | Magnitudes de la geometría representada; no son cantidades de material, obra, compra, capacidad útil ni fabricación. En geometrías compuestas se suman superficies y volúmenes de partes y pueden existir solapes no depurados. | Envolventes de equipos | Depósito de nitrógeno · blanco satinado de referencia | referencia_fotografica_provisional | equipment_white_tank_photo | [0.94,0.94,0.925] | 0.43 | 0.1 | Fotografías reales aportadas el 08/09/2026, sin fecha de toma ni emplazamiento verificados. Depósitos esbeltos blancos en las fotografías 01, 02, 04 y 06. Las bandas cambian entre instalaciones; no se trasladan colores de servicio, proporciones ni apoyos. Tono y parámetros de visualización orientativos; no especifican pintura, aleación ni dimensiones. | Equipos; Zona de separación de aire; BIM · Envolventes de equipos | ["found_0904_05e45d36ea4f96","found_0904_cbe5e32142275f","found_0904_0858fe779cb4ca","found_0904_79cb89b98841f0","found_0904_8347a0e234c768","found_0904_625ff173a269a3","found_0904_81ea899e189605","found_0904_1765e5f8dc4f36","found_0904_4f2b61caf5b971","found_0904_655b3ae9ebe287"] | Correspondencia documental; no verifica anclajes ni cotas de montaje. | 287.2 | 308.627 | {"source":{"documentId":"EQ-CARGAS-20260825","title":"Plano del fabricante: cargas de equipos","sheet":"Espacio modelo","date":"2026-08-25","componentSourceHandles":["42F","434"]},"heightSource":{"documentId":"EQ-CARGAS-20260825","title":"Plano del fabricante: cargas de equipos","sheet":"Espacio modelo","date":"2026-08-25"},"revision":"Detalle en planta de 2026-04-30 coordinado de forma preliminar con envolventes y alturas de 2026-08-25","horizontalStatus":"derivado","verticalRule":"Altura total documentada: 22,027 m y diámetro exterior 3,828 m. Para hacer visibles los apoyos se adopta provisionalmente una altura de apoyo de 0,60 m; envolvente cilíndrica desde Z = 0,60 hasta 22,027 m.","status":"Submalla exacta; interpretación funcional y cotas parciales provisionales.","unconfirmedDimensions":["Altura de apoyo de 0,60 m no acotada: hipótesis gráfica.","La planta de los apoyos no confirma su sección ni su construcción a lo largo de la altura.","Geometría de fondos curvos, faldón, soldaduras y espesores sin definir. No se inventan casquetes."],"issues":[],"material":"No especificado","quantityUse":"Magnitudes de la geometría representada; no son cantidades de material, obra, compra, capacidad útil ni fabricación. En geometrías compuestas se suman superficies y volúmenes de partes y pueden existir solapes no depurados.","partsAreBOM":false,"sourceInsertHandle":"83561","partCount":1,"sourcePartHandles":[{"partId":"SV1801A--body","sourceHandles":["42F","434"]},{"partId":"SV1801A--support-01","sourceHandles":["69AB8"]},{"partId":"SV1801A--support-02","sourceHandles":["69ABD"]},{"partId":"SV1801A--support-03","sourceHandles":["69AC2"]},{"partId":"SV1801A--support-04","sourceHandles":["69AC7"]}],"actualExtentManufacturerAxesM":[3.828,3.828,22.027],"sourcePartId":"SV1801A--body","sourceHandles":["42F","434"]} | {"documentId":"LHD2609-JG00100-20260904","title":"Cimentaciones y pedestales de equipos · revisión recibida 04/09/2026","date":"2026-09-04","sheet":"7 / 7-7","sourceHandles":["1FEDA","1FF68"]} | equipmentComponent | SV1801A | Depósito de nitrógeno líquido SV1801A | IfcTank | {"documented":[{"label":"Diámetro exterior del contorno CAD","value":3.828,"unit":"m","source":"EQ-CARGAS-20260825 · contorno CAD · handles 42F","status":"derivado"},{"label":"Altura acotada","value":22.027,"unit":"m","source":"EQ-CARGAS-20260825 · handle 434","status":"documentado"},{"label":"Cota relativa de la superficie de apoyo","value":0.5,"unit":"m","source":"LHD2609-JG00100-20260904 · sección 7 / 7-7 · 1FEDA, 1FF68","status":"documentado"}],"geometry":[{"label":"Extensión de la malla en X","value":3.827938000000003,"unit":"m","source":"Geometría releída del IFC; datum absoluto de proceso provisional","status":"derivado"},{"label":"Extensión de la malla en Y","value":3.827936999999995,"unit":"m","source":"Geometría releída del IFC; datum absoluto de proceso provisional","status":"derivado"},{"label":"Extensión de la malla en Z","value":22.026999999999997,"unit":"m","source":"Geometría releída del IFC; datum absoluto de proceso provisional","status":"derivado"},{"label":"Cota inferior de visualización","value":286.6,"unit":"m","source":"Geometría releída del IFC; datum absoluto de proceso provisional","status":"derivado"},{"label":"Cota superior de visualización","value":308.627,"unit":"m","source":"Geometría releída del IFC; datum absoluto de proceso provisional","status":"derivado"}],"notes":["Las extensiones de la malla se miden en los ejes del proyecto tras el giro de implantación; no sustituyen las dimensiones locales del fabricante.","La envolvente, su volumen y los espesores de visualización no son volúmenes de material ni cantidades de compra, construcción o fabricación.","Las dimensiones documentadas distinguen cotas explícitas y medidas extraídas de contornos CAD; las dimensiones geométricas describen únicamente la malla publicada.","Las extensiones de la malla refinada y las dimensiones documentadas del contorno o bastidor tienen distinto alcance; las cotas parciales del detalle son provisionales."]} | {"Estado de la planta":"Derivado del CAD y del giro de implantación","Nivel relativo del apoyo (m)":0.5,"Estado del nivel relativo":"Documentado en el plano de cimentaciones","Cero absoluto de visualización (m)":286.1,"Estado del cero absoluto":"Provisional","Cota del apoyo de visualización (m)":286.6,"Desplazamiento aplicado a la malla (m)":0.5000000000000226,"Criterio":"Nivel de apoyo relativo documentado. Se adopta el cero de proceso a 286,10 m solo para visualización; la equivalencia absoluta no está confirmada. No se añade un espesor de montaje sin cota del fabricante."} | ["Cilindro envolvente de altura total; no se dispone de la forma de los fondos, espesores ni componentes internos. El volumen geométrico no es capacidad útil.","Altura de apoyo de 0,60 m no acotada: hipótesis gráfica.","La planta de los apoyos no confirma su sección ni su construcción a lo largo de la altura.","Geometría de fondos curvos, faldón, soldaduras y espesores sin definir. No se inventan casquetes.","Cuatro pedestales DZ7 por tanque; el acabado superior de grout termina en +0,500. La cota -0,200 de planta no concuerda con -1,000 en la cara superior de la zapata de sección.","El cero absoluto de la revisión no está definido; 286,10 m sigue siendo una hipótesis de coordinación.","Se alinea el punto inferior del conjunto del equipo, incluidos los pies ya representados, con la superficie de apoyo terminada; no se añade un espesor de calzos, placa o grout del fabricante no documentado."] | {"revision":"Detalle en planta de 2026-04-30 coordinado de forma preliminar con envolventes y alturas de 2026-08-25","status":"provisional","verticalRule":"Altura total documentada: 22,027 m y diámetro exterior 3,828 m. Para hacer visibles los apoyos se adopta provisionalmente una altura de apoyo de 0,60 m; envolvente cilíndrica desde Z = 0,60 hasta 22,027 m.","partCount":5,"source":{"documentId":"EQ-IMPLANTACION-20260430","title":"Plano del fabricante: implantación de equipos","sheet":"LHD2609-GD01000 · espacio modelo","date":"2026-04-30"},"heightSource":{"documentId":"EQ-CARGAS-20260825","title":"Plano del fabricante: cargas de equipos","sheet":"Espacio modelo","date":"2026-08-25"},"unconfirmedDimensions":["Altura de apoyo de 0,60 m no acotada: hipótesis gráfica.","La planta de los apoyos no confirma su sección ni su construcción a lo largo de la altura.","Geometría de fondos curvos, faldón, soldaduras y espesores sin definir. No se inventan casquetes."],"quantityUse":"Magnitudes de la geometría representada; no son cantidades de material, obra, compra, capacidad útil ni fabricación. En geometrías compuestas se suman superficies y volúmenes de partes y pueden existir solapes no depurados.","partsAreBOM":false} | outer_vessel_envelope | {"min":[34.463015,30.600052,1.6],"max":[38.290953,34.427989,23.627]} | {"boundingBoxM":{"min":[34.463015,30.600052,1.6],"max":[38.290953,34.427989,23.627]},"extentsM":[3.827938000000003,3.827936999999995,22.026999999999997],"meshSurfaceM2":288.3822067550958,"meshVolumeM3":247.2829421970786,"closedSolid":true,"windingConsistent":true,"basis":"Submalla exacta de los triángulos del modelo IFC coordinado; separación de componentes sin transformación ni retesselación."} | ["Altura de apoyo de 0,60 m no acotada: hipótesis gráfica.","La planta de los apoyos no confirma su sección ni su construcción a lo largo de la altura.","Geometría de fondos curvos, faldón, soldaduras y espesores sin definir. No se inventan casquetes.","La separación gráfica no aporta cotas de fabricación ni identifica piezas internas no documentadas.","Los materiales y acabados permanecen provisionales; las fotografías públicas solo orientan la apariencia."] | {"id":"SV1801A","sourcePartId":"SV1801A--body","name":"Envolvente cilíndrica del depósito","role":"outer_vessel_envelope","classificationStatus":"provisional","classificationBasis":"Rol del subvolumen gráfico según el activo de detalle; identidad de fabricación no confirmada.","parentEquipmentId":"SV1801A","parentEquipmentGuid":"1EEV2pFbzMUQXwXeX6CZae","isAssemblyIdentityCarrier":true,"sourceFaceRange":[0,764],"sourceCurrentFaceIndices":[0,1,2,3,4,5,6,7,8,9,10,11,12,13,14,15,16,17,18,19,20,21,22,23,24,25,26,27,28,29,30,31,32,33,34,35,36,37,38,39,40,41,42,43,44,45,46,47,48,49,50,51,52,53,54,55,56,57,58,59,60,61,62,63,64,65,66,67,68,69,70,71,72,73,74,75,76,77,78,79,80,81,82,83,84,85,86,87,88,89,90,91,92,93,94,95,96,97,98,99,100,101,102,103,104,105,106,107,108,109,110,111,112,113,114,115,116,117,118,119,120,121,122,123,124,125,126,127,128,129,130,131,132,133,134,135,136,137,138,139,140,141,142,143,144,145,146,147,148,149,150,151,152,153,154,155,156,157,158,159,160,161,162,163,164,165,166,167,168,169,170,171,172,173,174,175,176,177,178,179,180,181,182,183,184,185,186,187,188,189,190,191,192,193,194,195,196,197,198,199,200,201,202,203,204,205,206,207,208,209,210,211,212,213,214,215,216,217,218,219,220,221,222,223,224,225,226,227,228,229,230,231,232,233,234,235,236,237,238,239,240,241,242,243,244,245,246,247,248,249,250,251,252,253,254,255,256,257,258,259,260,261,262,263,264,265,266,267,268,269,270,271,272,273,274,275,276,277,278,279,280,281,282,283,284,285,286,287,288,289,290,291,292,293,294,295,296,297,298,299,300,301,302,303,304,305,306,307,308,309,310,311,312,313,314,315,316,317,318,319,320,321,322,323,324,325,326,327,328,329,330,331,332,333,334,335,336,337,338,339,340,341,342,343,344,345,346,347,348,349,350,351,352,353,354,355,356,357,358,359,360,361,362,363,364,365,366,367,368,369,370,371,372,373,374,375,376,377,378,379,380,381,382,383,384,385,386,387,388,389,390,391,392,393,394,395,396,397,398,399,400,401,402,403,404,405,406,407,408,409,410,411,412,413,414,415,416,417,418,419,420,421,422,423,424,425,426,427,428,429,430,431,432,433,434,435,436,437,438,439,440,441,442,443,444,445,446,447,448,449,450,451,452,453,454,455,456,457,458,459,460,461,462,463,464,465,466,467,468,469,470,471,472,473,474,475,476,477,478,479,480,481,482,483,484,485,486,487,488,489,490,491,492,493,494,495,496,497,498,499,500,501,502,503,504,505,506,507,508,509,510,511,512,513,514,515,516,517,518,519,520,521,522,523,524,525,526,527,528,529,530,531,532,533,534,535,536,537,538,539,540,541,542,543,544,545,546,547,548,549,550,551,552,553,554,555,556,557,558,559,560,561,562,563,564,565,566,567,568,569,570,571,572,573,574,575,576,577,578,579,580,581,582,583,584,585,586,587,588,589,590,591,592,593,594,595,596,597,598,599,600,601,602,603,604,605,606,607,608,609,610,611,612,613,614,615,616,617,618,619,620,621,622,623,624,625,626,627,628,629,630,631,632,633,634,635,636,637,638,639,640,641,642,643,644,645,646,647,648,649,650,651,652,653,654,655,656,657,658,659,660,661,662,663,664,665,666,667,668,669,670,671,672,673,674,675,676,677,678,679,680,681,682,683,684,685,686,687,688,689,690,691,692,693,694,695,696,697,698,699,700,701,702,703,704,705,706,707,708,709,710,711,712,713,714,715,716,717,718,719,720,721,722,723,724,725,726,727,728,729,730,731,732,733,734,735,736,737,738,739,740,741,742,743,744,745,746,747,748,749,750,751,752,753,754,755,756,757,758,759,760,761,762,763],"sourceMeshSha256":"7b60c904c9d84d22fded9be34af09a09a9c198ec8e75e61902634d5e4064c761","sourceVertexIndices":[0,1,2,3,4,5,6,7,8,9,10,11,12,13,14,15,16,17,18,19,20,21,22,23,24,25,26,27,28,29,30,31,32,33,34,35,36,37,38,39,40,41,42,43,44,45,46,47,48,49,50,51,52,53,54,55,56,57,58,59,60,61,62,63,64,65,66,67,68,69,70,71,72,73,74,75,76,77,78,79,80,81,82,83,84,85,86,87,88,89,90,91,92,93,94,95,96,97,98,99,100,101,102,103,104,105,106,107,108,109,110,111,112,113,114,115,116,117,118,119,120,121,122,123,124,125,126,127,128,129,130,131,132,133,134,135,136,137,138,139,140,141,142,143,144,145,146,147,148,149,150,151,152,153,154,155,156,157,158,159,160,161,162,163,164,165,166,167,168,169,170,171,172,173,174,175,176,177,178,179,180,181,182,183,184,185,186,187,188,189,190,191,192,193,194,195,196,197,198,199,200,201,202,203,204,205,206,207,208,209,210,211,212,213,214,215,216,217,218,219,220,221,222,223,224,225,226,227,228,229,230,231,232,233,234,235,236,237,238,239,240,241,242,243,244,245,246,247,248,249,250,251,252,253,254,255,256,257,258,259,260,261,262,263,264,265,266,267,268,269,270,271,272,273,274,275,276,277,278,279,280,281,282,283,284,285,286,287,288,289,290,291,292,293,294,295,296,297,298,299,300,301,302,303,304,305,306,307,308,309,310,311,312,313,314,315,316,317,318,319,320,321,322,323,324,325,326,327,328,329,330,331,332,333,334,335,336,337,338,339,340,341,342,343,344,345,346,347,348,349,350,351,352,353,354,355,356,357,358,359,360,361,362,363,364,365,366,367,368,369,370,371,372,373,374,375,376,377,378,379,380,381,382,383],"separationMethod":"Partición exacta de triángulos existentes; coordenadas y orientación de caras conservadas.","quantityUse":"Magnitudes geométricas del subvolumen; no son cantidades netas de material, fabricación, suministro o capacidad."} | {"id":"SV1801A","name":"Depósito de nitrógeno líquido SV1801A","relationship":"identity_carrier_with_child_components","parentShapeMeaning":"La forma del objeto que conserva el ID del equipo es únicamente su componente principal; el conjunto completo requiere sus hijos."} | {"kind":"assembly_documentation","parentEquipmentId":"SV1801A","directAnchorageVerified":false,"note":"La relación del conjunto con cimentaciones se conserva en el objeto que mantiene el ID del equipo; no se atribuye fijación directa a cada subcomponente."} | Documento de implantación y apoyo del conjunto padre; no acredita fijación individual de este componente. | ["SV1801A","SV1801A--support-01","SV1801A--support-02","SV1801A--support-03","SV1801A--support-04"] | ["SV1801A--support-01","SV1801A--support-02","SV1801A--support-03","SV1801A--support-04"] | ["SV1801A--body","SV1801A--support-01","SV1801A--support-02","SV1801A--support-03","SV1801A--support-04"] | {"Referencia en el plano del fabricante":"7","Identificador del fabricante o del modelo":"SV1801A","Documento de origen":"Plano del fabricante: cargas de equipos · 2026-08-25 · Espacio modelo; número de plano no identificado","Documento CAD derivado":"Conversión DXF del plano de cargas de equipos · 2026-08-25 · espacio modelo","Capa CAD de referencia":"Anotaciones y contornos de equipos","Identificadores CAD del contorno (handles)":"42F","Identificador CAD de la cota de altura (handle)":"434","Cota de altura del fabricante (traducción)":"Altura del equipo: 22.027m","Altura (m)":22.027,"Origen de las dimensiones":"Plano de cargas del fabricante de 2026-08-25: lectura directa del contorno CAD cerrado y de la cota de altura del equipo.","Grado de definición":"Planta derivada del CAD, altura total documentada y alturas parciales provisionales.","Alcance de la geometría":"Geometría compuesta con perfiles CAD y distribución vertical provisional; véase Detalle geométrico.","Origen de la posición":"Punto de referencia del fabricante: entidad CIRCLE, handle 98, en la esquina inferior izquierda de la zona de equipos. Los ejes X e Y son locales y se giran para su implantación UTM.","Hipótesis de modelado":"Nivel de apoyo relativo documentado. Se adopta el cero de proceso a 286,10 m solo para visualización; la equivalencia absoluta no está confirmada. No se añade un espesor de montaje sin cota del fabricante.","Observaciones":"No se dispone de la geometría de los fondos curvos superior e inferior: se utiliza una envolvente cilíndrica de altura total. El radio del eje de referencia, 1 620 mm, y el de la cimentación, 2 400 mm, no son el radio exterior adoptado. Carga variable indicada: 121 500 kg.","Masa propia indicada (kg)":49100,"Diámetro (m)":3.828,"Carga variable indicada por el fabricante (kg)":121500,"Dimensiones de la plataforma de equipos (m)":"27 × 57 m; dimensiones acotadas en el plano general.","Implantación de la plataforma de equipos":"El punto de referencia del fabricante coincide con la esquina suroeste de la zona de equipos. Giro local de −7,82824° para la implantación en coordenadas UTM.","Estado de la cota de instalación":"Nivel de apoyo relativo documentado. Se adopta el cero de proceso a 286,10 m solo para visualización; la equivalencia absoluta no está confirmada. No se añade un espesor de montaje sin cota del fabricante.","Convención de coordenadas":"Coordenadas locales del proyecto en metros. Añadir (729400, 4301550, 285) para recuperar las coordenadas UTM y las cotas del plano.","Identificador del objeto":"SV1801A","Disciplina":"Equipos","Clase IFC":"IfcTank","Fase del modelo":"Revisión de la zona de separación de aire · septiembre de 2026","Representación geométrica IFC":"Sólido IFC4 mediante malla triangular cerrada","Aplicabilidad a mediciones":"Magnitudes de la geometría representada; no son cantidades de material, obra, compra, capacidad útil ni fabricación. En geometrías compuestas se suman superficies y volúmenes de partes y pueden existir solapes no depurados.","Material":"No especificado","Estado de la información":"provisional","Detalle geométrico":"derivado","Incidencias del detalle":["Nivel de apoyo relativo documentado. Se adopta el cero de proceso a 286,10 m solo para visualización; la equivalencia absoluta no está confirmada. No se añade un espesor de montaje sin cota del fabricante.","Cilindro envolvente de altura total; no se dispone de la forma de los fondos, espesores ni componentes internos. El volumen geométrico no es capacidad útil.","Altura de apoyo de 0,60 m no acotada: hipótesis gráfica.","La planta de los apoyos no confirma su sección ni su construcción a lo largo de la altura.","Geometría de fondos curvos, faldón, soldaduras y espesores sin definir. No se inventan casquetes."],"Extensión X del conjunto refinado en ejes del fabricante (m)":3.8279999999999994,"Extensión Y del conjunto refinado en ejes del fabricante (m)":3.8279999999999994,"Nivel relativo de apoyo documentado (m)":0.5,"Fuente del nivel de apoyo":{"documentId":"LHD2609-JG00100-20260904","title":"Cimentaciones y pedestales de equipos · revisión recibida 04/09/2026","date":"2026-09-04","sheet":"7 / 7-7","sourceHandles":["1FEDA","1FF68"]},"Criterio de instalación":"Nivel de apoyo relativo documentado. Se adopta el cero de proceso a 286,10 m solo para visualización; la equivalencia absoluta no está confirmada. No se añade un espesor de montaje sin cota del fabricante."} | Subvolumen --body explícitamente identificado en el activo de detalle. | {"receivedDate":"2026-09-08","referenceIds":["jinhong-official-asu","xinrui-jinhong-vaporizers","foto-usuario-20260908-01","foto-usuario-20260908-02","foto-usuario-20260908-04","foto-usuario-20260908-06"],"use":"Color, brillo y lectura de superficies. Sin cambios de geometría o dimensiones.","geometryConfirmedByPhotos":false} | 7 | Conversión DXF del plano de cargas de equipos · 2026-08-25 · espacio modelo | Anotaciones y contornos de equipos | 42F | 434 | Altura del equipo: 22.027m | Plano de cargas del fabricante de 2026-08-25: lectura directa del contorno CAD cerrado y de la cota de altura del equipo. | Planta derivada del CAD, altura total documentada y alturas parciales provisionales. | Geometría compuesta con perfiles CAD y distribución vertical provisional; véase Detalle geométrico. | Punto de referencia del fabricante: entidad CIRCLE, handle 98, en la esquina inferior izquierda de la zona de equipos. Los ejes X e Y son locales y se giran para su implantación UTM. | Nivel de apoyo relativo documentado. Se adopta el cero de proceso a 286,10 m solo para visualización; la equivalencia absoluta no está confirmada. No se añade un espesor de montaje sin cota del fabricante. | No se dispone de la geometría de los fondos curvos superior e inferior: se utiliza una envolvente cilíndrica de altura total. El radio del eje de referencia, 1 620 mm, y el de la cimentación, 2 400 mm, no son el radio exterior adoptado. Carga variable indicada: 121 500 kg. | 49100 | 121500 | 27 × 57 m; dimensiones acotadas en el plano general. | El punto de referencia del fabricante coincide con la esquina suroeste de la zona de equipos. Giro local de −7,82824° para la implantación en coordenadas UTM. | Coordenadas locales del proyecto en metros. Añadir (729400, 4301550, 285) para recuperar las coordenadas UTM y las cotas del plano. | derivado | ["Nivel de apoyo relativo documentado. Se adopta el cero de proceso a 286,10 m solo para visualización; la equivalencia absoluta no está confirmada. No se añade un espesor de montaje sin cota del fabricante.","Cilindro envolvente de altura total; no se dispone de la forma de los fondos, espesores ni componentes internos. El volumen geométrico no es capacidad útil.","Altura de apoyo de 0,60 m no acotada: hipótesis gráfica.","La planta de los apoyos no confirma su sección ni su construcción a lo largo de la altura.","Geometría de fondos curvos, faldón, soldaduras y espesores sin definir. No se inventan casquetes."] | 3.828 | 0.5 | Envolvente cilíndrica del depósito | Envolventes de equipos | unknown | equipment_white_tank | {"documentId":"EQ-CARGAS-20260825","title":"Plano del fabricante: cargas de equipos","sheet":"Espacio modelo","date":"2026-08-25","componentSourceHandles":["42F","434"]} | Submalla de triángulos existentes; no hay nueva posición ni nuevas caras. | Cotas globales del conjunto conservadas aparte; las dimensiones de esta ficha son de la submalla. | Coordinación del conjunto padre; anclaje directo individual no acreditado. | Superficie y volumen geométricos brutos; no constituyen cantidades netas de obra, material o fabricación. | Plano general y dimensiones globales de SV1801A; no se asignan esas dimensiones globales a este componente. | {"documentId":"EQ-CARGAS-20260825","title":"Plano del fabricante: cargas de equipos","sheet":"Espacio modelo","date":"2026-08-25"} | Detalle en planta de 2026-04-30 coordinado de forma preliminar con envolventes y alturas de 2026-08-25 | Altura total documentada: 22,027 m y diámetro exterior 3,828 m. Para hacer visibles los apoyos se adopta provisionalmente una altura de apoyo de 0,60 m; envolvente cilíndrica desde Z = 0,60 hasta 22,027 m. | Submalla exacta; interpretación funcional y cotas parciales provisionales. | ["Altura de apoyo de 0,60 m no acotada: hipótesis gráfica.","La planta de los apoyos no confirma su sección ni su construcción a lo largo de la altura.","Geometría de fondos curvos, faldón, soldaduras y espesores sin definir. No se inventan casquetes."] | [] | No especificado | Magnitudes de la geometría representada; no son cantidades de material, obra, compra, capacidad útil ni fabricación. En geometrías compuestas se suman superficies y volúmenes de partes y pueden existir solapes no depurados. | no | 83561 | 1 | [{"partId":"SV1801A--body","sourceHandles":["42F","434"]},{"partId":"SV1801A--support-01","sourceHandles":["69AB8"]},{"partId":"SV1801A--support-02","sourceHandles":["69ABD"]},{"partId":"SV1801A--support-03","sourceHandles":["69AC2"]},{"partId":"SV1801A--support-04","sourceHandles":["69AC7"]}] | [3.828,3.828,22.027] | SV1801A--body | ["42F","434"] | ["jinhong-official-asu","xinrui-jinhong-vaporizers","foto-usuario-20260908-01","foto-usuario-20260908-02","foto-usuario-20260908-04","foto-usuario-20260908-06"] | 2026-09-08
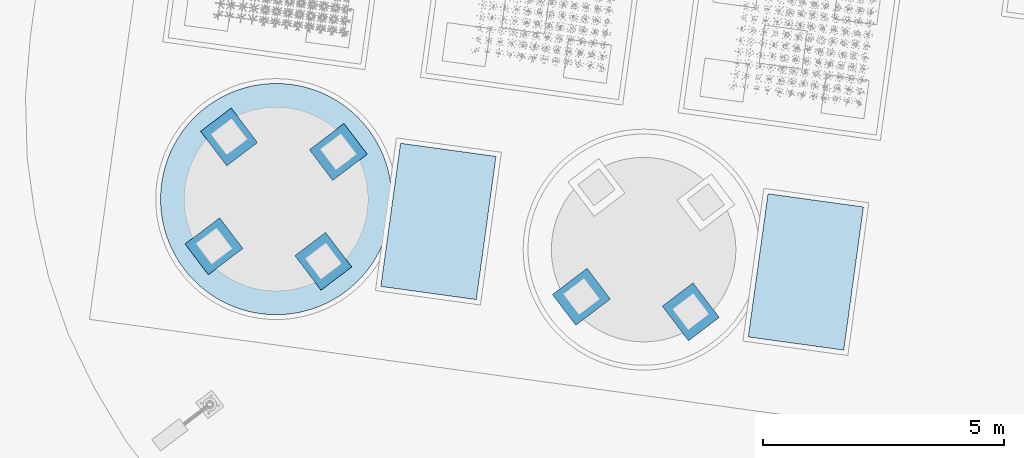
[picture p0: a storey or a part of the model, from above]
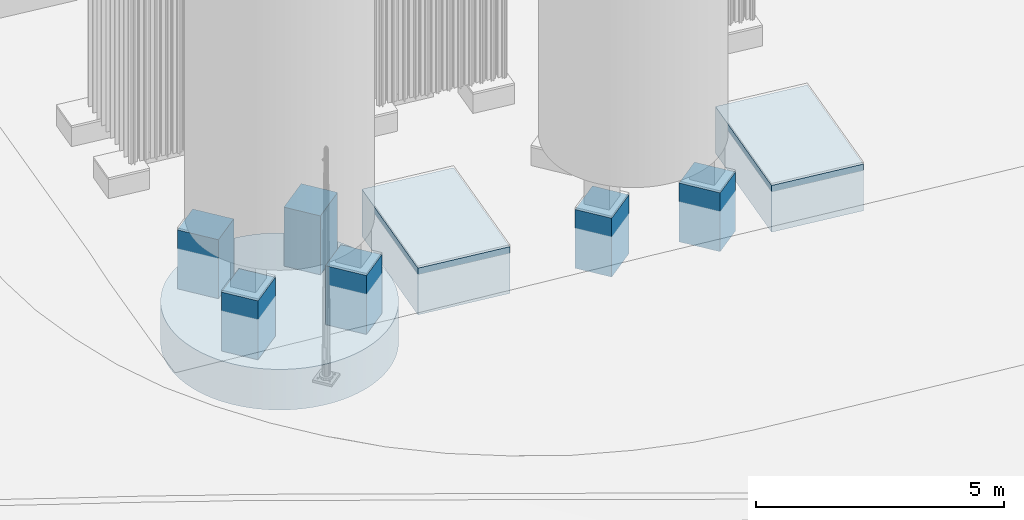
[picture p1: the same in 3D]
Properties of the parts of a building model (IFC4), part 112 of 134

# IfcTank (3)
Name | Description = category = Categoria = Funcion | Document | Extensión de la malla en X (m) = Extensión de la malla en Y (m) = ExtensionX (m) = ExtensionY (m) | Extensión de la malla en Z (m) = ExtensionZ (m) | SuperficieDeLaMalla (m2) | VolumenGeometrico (m3) | buildingId | buildingName | level | dimensions | JH_InformacionBIM, source = DocumentoFuente | positioning = PosicionYEstado | JH_InformacionBIM, issues = IncidenciasPendientes | geometryMetrics | visualLayer | materialAppearance | componentSeparation | visualizationIdentity | classification | layerId = IdentificadorCapa | appearance | Documento de origen | Diámetro (m) | Altura (m) | Identificador del objeto = Identificador | Disciplina | Fase del modelo | Aplicabilidad a mediciones | Capa BIM = NombreCapa | Acabado de visualización = Acabado | Estado del acabado = Estado | Perfil | ColorRGB | Rugosidad | Metallicidad | Referencia | Group | ElementosDeCimentacion = foundationIds | Relacion | Cota inferior de visualización (m) | Cota superior de visualización (m) | detailGeometry | installationSource = Fuente del nivel de apoyo | representationKind | parentEquipmentId = Identificador del fabricante o del modelo = Identificador del elemento = Identificador del equipo padre | parentEquipmentName = Equipo padre | parentEquipmentIfcClass | parentEquipmentDimensions | parentEquipmentPositioning | parentEquipmentIssues | parentEquipmentDetail | componentRole = Rol del componente | assemblyBBox | assemblyGeometryMetrics | manufacturerDetailsPending | component | assembly | foundationRelationship | installationSourceScope | componentIds | childComponentIds | sourcePartIds | parentEquipmentProperties | mainComponentSelectionBasis | photoAppearanceReview | Referencia en el plano del fabricante | Documento CAD derivado | Capa CAD de referencia | Identificadores CAD del contorno (handles) | Identificador CAD de la cota de altura (handle) | Cota de altura del fabricante (traducción) | Origen de las dimensiones | Grado de definición | Alcance de la geometría | Origen de la posición | Hipótesis de modelado = Estado de la cota de instalación = Criterio de instalación | Observaciones | Masa propia indicada (kg) | Carga variable indicada por el fabricante (kg) | Dimensiones de la plataforma de equipos (m) | Implantación de la plataforma de equipos | Convención de coordenadas | Detalle geométrico = horizontalStatus | Incidencias del detalle | Extensión X del conjunto refinado en ejes del fabricante (m) = Extensión Y del conjunto refinado en ejes del fabricante (m) | Nivel relativo de apoyo documentado (m) | Componente | Capa de visualización | Estado del material | Perfil visual del material | Fuente del componente = JH_DetalleGeometrico, source | Criterio de partición | Criterio de las dimensiones | Relación con cimentaciones | Aplicabilidad de las mediciones | Referencia dimensional del conjunto | heightSource | revision | verticalRule | status | unconfirmedDimensions | JH_DetalleGeometrico, issues | material | quantityUse | partsAreBOM | sourceInsertHandle | partCount | sourcePartHandles | actualExtentManufacturerAxesM | sourcePartId | sourceHandles | Fotografias | FechaRevision
Depósito de nitrógeno líquido SV1801B · Envolvente cilíndrica del depósito | Componente de equipo · envolvente exterior | Plano del fabricante: cargas de equipos; Plano del fabricante: implantación de equipos · referencia E7; Cimentaciones de equipos y pedestales del fabricante · revisión recibida 04/09/2026; Fotografía de referencia aportada · 01; Fotografía de referencia aportada · 02; Fotografía de referencia aportada · 04; Fotografía de referencia aportada · 06 | 3.82794 | 21.427 | 280.684 | 246.557 | process_plant | Planta de proceso | Apoyo relativo +0.500 m; cero absoluto provisional | {"documented":[{"label":"Referencia dimensional del conjunto","value":"Plano general y dimensiones globales de SV1801B; no se asignan esas dimensiones globales a este componente.","unit":"","source":"EQ-CARGAS-20260825 · Espacio modelo","status":"referencia_del_conjunto"}],"geometry":[{"label":"Extensión de la malla en X","value":3.8279369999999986,"unit":"m","source":"Geometría releída del IFC; datum absoluto de proceso provisional","status":"derivado"},{"label":"Extensión de la malla en Y","value":3.8279379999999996,"unit":"m","source":"Geometría releída del IFC; datum absoluto de proceso provisional","status":"derivado"},{"label":"Extensión de la malla en Z","value":21.427,"unit":"m","source":"Geometría releída del IFC; datum absoluto de proceso provisional","status":"derivado"},{"label":"Cota inferior de visualización","value":287.2,"unit":"m","source":"Geometría releída del IFC; datum absoluto de proceso provisional","status":"derivado"},{"label":"Cota superior de visualización","value":308.627,"unit":"m","source":"Geometría releída del IFC; datum absoluto de proceso provisional","status":"derivado"}],"notes":["Las dimensiones del equipo completo se conservan en parentEquipmentDimensions.","Las extensiones en X/Y son de los ejes del modelo y no sustituyen cotas locales de fabricación.","No se infieren espesores de chapa, tolerancias ni dimensiones de piezas a partir de la partición."]} | {"documentId":"EQ-CARGAS-20260825","title":"Plano del fabricante: cargas de equipos","sheet":"Espacio modelo","date":"2026-08-25","componentSourceHandles":["438","273B"]} | {"Estado de la planta":"Derivado del CAD y del giro de implantación","Nivel relativo del apoyo (m)":0.5,"Estado del nivel relativo":"Documentado en el plano de cimentaciones","Cero absoluto de visualización (m)":286.1,"Estado del cero absoluto":"Provisional","Cota del apoyo de visualización (m)":286.6,"Desplazamiento aplicado a la malla (m)":0.5000000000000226,"Criterio":"Nivel de apoyo relativo documentado. Se adopta el cero de proceso a 286,10 m solo para visualización; la equivalencia absoluta no está confirmada. No se añade un espesor de montaje sin cota del fabricante.","horizontalStatus":"derivado_del_conjunto","verticalStatus":"derivado_del_conjunto","coordinateSystem":"model_local_m","parentEquipmentId":"SV1801B","transformApplied":false,"note":"Coordenadas copiadas exactamente del equipo coordinado; no se ha movido, girado, elevado ni reescalado este componente.","foundationRelationship":"El apoyo y las cotas de instalación se documentan para el conjunto padre. Esta submalla no acredita un anclaje directo.","meshMinimumAbsoluteElevationM":287.2,"assemblyPlacementField":"parentEquipmentPositioning"} | ["Componente separado de una reconstrucción documental del conjunto. Las alturas y detalles parciales conservan las limitaciones del fabricante registradas en parentEquipmentIssues.","Esta representación exterior no crea una chapa hueca ni añade componentes internos no documentados.","La pertenencia al conjunto no demuestra apoyo o anclaje directo a la cimentación."] | {"boundingBoxM":{"min":[42.091258,29.551281,2.2],"max":[45.919195,33.379219,23.627]},"extentsM":[3.827937,3.827938,21.427],"meshSurfaceM2":280.683653,"meshVolumeM3":246.55715,"closedSolid":true,"basis":"Geometría de coordinación. Los volúmenes de referencia y subcomponentes no son cantidades de material ni componentes de fabricación certificados."} | {"id":"equipment_enclosures","name":"Envolventes de equipos"} | {"profileId":"equipment_white_tank_photo","name":"Depósito de nitrógeno · blanco satinado de referencia","materialName":"No especificado","physicalMaterialStatus":"unknown","physicalMaterialSource":"Sin especificación de material en la documentación revisada","appearanceStatus":"referencia_fotografica_provisional","appearanceBasis":"Fotografías reales aportadas el 08/09/2026, sin fecha de toma ni emplazamiento verificados. Depósitos esbeltos blancos en las fotografías 01, 02, 04 y 06. Las bandas cambian entre instalaciones; no se trasladan colores de servicio, proporciones ni apoyos. Tono y parámetros de visualización orientativos; no especifican pintura, aleación ni dimensiones.","appearanceReferences":["jinhong-official-asu","xinrui-jinhong-vaporizers"],"note":"El perfil visual no confirma material, grado ni acabado del componente."} | {"status":"componente_independiente","note":"Objeto independiente seleccionable. Las caras se asignan una sola vez entre todos los componentes del conjunto.","parentEquipmentId":"SV1801B","isAssemblyIdentityCarrier":true} | {"elementId":"SV1801B","ifcGuid":"206t194YPQWO6Wa6jSddOs","ifcClass":"IfcTank","buildingId":"process_plant","buildingName":"Planta de proceso","sourceDocumentId":"EQ-CARGAS-20260825","sourceRepresentationKind":"equipmentComponent"} | {"layerId":"equipment_enclosures","layerName":"Envolventes de equipos","role":"Componente de equipo · envolvente exterior","basis":"Clasificación por función del elemento; no modifica las especificaciones documentales."} | equipment_enclosures | {"profileId":"equipment_white_tank_photo","name":"Depósito de nitrógeno · blanco satinado de referencia","status":"referencia_fotografica_provisional","basis":"Fotografías reales aportadas el 08/09/2026, sin fecha de toma ni emplazamiento verificados. Depósitos esbeltos blancos en las fotografías 01, 02, 04 y 06. Las bandas cambian entre instalaciones; no se trasladan colores de servicio, proporciones ni apoyos. Tono y parámetros de visualización orientativos; no especifican pintura, aleación ni dimensiones.","physicalMaterialUnchanged":true} | Plano del fabricante: cargas de equipos · 2026-08-25 · Espacio modelo; número de plano no identificado | 3.828 | 22.027 | SV1801B | Envolventes de equipos | Revisión de la zona de separación de aire · septiembre de 2026 | Magnitudes de la geometría representada; no son cantidades de material, obra, compra, capacidad útil ni fabricación. En geometrías compuestas se suman superficies y volúmenes de partes y pueden existir solapes no depurados. | Envolventes de equipos | Depósito de nitrógeno · blanco satinado de referencia | referencia_fotografica_provisional | equipment_white_tank_photo | [0.94,0.94,0.925] | 0.43 | 0.1 | Fotografías reales aportadas el 08/09/2026, sin fecha de toma ni emplazamiento verificados. Depósitos esbeltos blancos en las fotografías 01, 02, 04 y 06. Las bandas cambian entre instalaciones; no se trasladan colores de servicio, proporciones ni apoyos. Tono y parámetros de visualización orientativos; no especifican pintura, aleación ni dimensiones. | Equipos; Zona de separación de aire; BIM · Envolventes de equipos | ["found_0904_1560ce06c6f620","found_0904_2674dba16f3e98","found_0904_73bf36418cda5f","found_0904_05dc0b2212108d","found_0904_6d4f95d05f13d2","found_0904_a3aab55a390f86","found_0904_2f52643828a88e","found_0904_8f98344bec99e5","found_0904_45f2f263423089","found_0904_d2da6dd42bcec3"] | Correspondencia documental; no verifica anclajes ni cotas de montaje. | 287.2 | 308.627 | {"source":{"documentId":"EQ-CARGAS-20260825","title":"Plano del fabricante: cargas de equipos","sheet":"Espacio modelo","date":"2026-08-25","componentSourceHandles":["438","273B"]},"heightSource":{"documentId":"EQ-CARGAS-20260825","title":"Plano del fabricante: cargas de equipos","sheet":"Espacio modelo","date":"2026-08-25"},"revision":"Detalle en planta de 2026-04-30 coordinado de forma preliminar con envolventes y alturas de 2026-08-25","horizontalStatus":"derivado","verticalRule":"Altura total documentada: 22,027 m y diámetro exterior 3,828 m. Para hacer visibles los apoyos se adopta provisionalmente una altura de apoyo de 0,60 m; envolvente cilíndrica desde Z = 0,60 hasta 22,027 m.","status":"Submalla exacta; interpretación funcional y cotas parciales provisionales.","unconfirmedDimensions":["Altura de apoyo de 0,60 m no acotada: hipótesis gráfica.","La planta de los apoyos no confirma su sección ni su construcción a lo largo de la altura.","Geometría de fondos curvos, faldón, soldaduras y espesores sin definir. No se inventan casquetes."],"issues":[],"material":"No especificado","quantityUse":"Magnitudes de la geometría representada; no son cantidades de material, obra, compra, capacidad útil ni fabricación. En geometrías compuestas se suman superficies y volúmenes de partes y pueden existir solapes no depurados.","partsAreBOM":false,"sourceInsertHandle":"85232","partCount":1,"sourcePartHandles":[{"partId":"SV1801B--body","sourceHandles":["438","273B"]},{"partId":"SV1801B--support-01","sourceHandles":["69AB8"]},{"partId":"SV1801B--support-02","sourceHandles":["69ABD"]},{"partId":"SV1801B--support-03","sourceHandles":["69AC2"]},{"partId":"SV1801B--support-04","sourceHandles":["69AC7"]}],"actualExtentManufacturerAxesM":[3.828,3.828,22.027],"sourcePartId":"SV1801B--body","sourceHandles":["438","273B"]} | {"documentId":"LHD2609-JG00100-20260904","title":"Cimentaciones y pedestales de equipos · revisión recibida 04/09/2026","date":"2026-09-04","sheet":"7 / 7-7","sourceHandles":["1FEDA","1FF68"]} | equipmentComponent | SV1801B | Depósito de nitrógeno líquido SV1801B | IfcTank | {"documented":[{"label":"Diámetro exterior del contorno CAD","value":3.828,"unit":"m","source":"EQ-CARGAS-20260825 · contorno CAD · handles 438","status":"derivado"},{"label":"Altura acotada","value":22.027,"unit":"m","source":"EQ-CARGAS-20260825 · handle 273B","status":"documentado"},{"label":"Cota relativa de la superficie de apoyo","value":0.5,"unit":"m","source":"LHD2609-JG00100-20260904 · sección 7 / 7-7 · 1FEDA, 1FF68","status":"documentado"}],"geometry":[{"label":"Extensión de la malla en X","value":3.8279369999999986,"unit":"m","source":"Geometría releída del IFC; datum absoluto de proceso provisional","status":"derivado"},{"label":"Extensión de la malla en Y","value":3.8279379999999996,"unit":"m","source":"Geometría releída del IFC; datum absoluto de proceso provisional","status":"derivado"},{"label":"Extensión de la malla en Z","value":22.026999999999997,"unit":"m","source":"Geometría releída del IFC; datum absoluto de proceso provisional","status":"derivado"},{"label":"Cota inferior de visualización","value":286.6,"unit":"m","source":"Geometría releída del IFC; datum absoluto de proceso provisional","status":"derivado"},{"label":"Cota superior de visualización","value":308.627,"unit":"m","source":"Geometría releída del IFC; datum absoluto de proceso provisional","status":"derivado"}],"notes":["Las extensiones de la malla se miden en los ejes del proyecto tras el giro de implantación; no sustituyen las dimensiones locales del fabricante.","La envolvente, su volumen y los espesores de visualización no son volúmenes de material ni cantidades de compra, construcción o fabricación.","Las dimensiones documentadas distinguen cotas explícitas y medidas extraídas de contornos CAD; las dimensiones geométricas describen únicamente la malla publicada.","Las extensiones de la malla refinada y las dimensiones documentadas del contorno o bastidor tienen distinto alcance; las cotas parciales del detalle son provisionales."]} | {"Estado de la planta":"Derivado del CAD y del giro de implantación","Nivel relativo del apoyo (m)":0.5,"Estado del nivel relativo":"Documentado en el plano de cimentaciones","Cero absoluto de visualización (m)":286.1,"Estado del cero absoluto":"Provisional","Cota del apoyo de visualización (m)":286.6,"Desplazamiento aplicado a la malla (m)":0.5000000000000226,"Criterio":"Nivel de apoyo relativo documentado. Se adopta el cero de proceso a 286,10 m solo para visualización; la equivalencia absoluta no está confirmada. No se añade un espesor de montaje sin cota del fabricante."} | ["Cilindro envolvente de altura total; no se dispone de la forma de los fondos, espesores ni componentes internos. El volumen geométrico no es capacidad útil.","Altura de apoyo de 0,60 m no acotada: hipótesis gráfica.","La planta de los apoyos no confirma su sección ni su construcción a lo largo de la altura.","Geometría de fondos curvos, faldón, soldaduras y espesores sin definir. No se inventan casquetes.","Cuatro pedestales DZ7 por tanque; el acabado superior de grout termina en +0,500. La cota -0,200 de planta no concuerda con -1,000 en la cara superior de la zapata de sección.","El cero absoluto de la revisión no está definido; 286,10 m sigue siendo una hipótesis de coordinación.","Se alinea el punto inferior del conjunto del equipo, incluidos los pies ya representados, con la superficie de apoyo terminada; no se añade un espesor de calzos, placa o grout del fabricante no documentado."] | {"revision":"Detalle en planta de 2026-04-30 coordinado de forma preliminar con envolventes y alturas de 2026-08-25","status":"provisional","verticalRule":"Altura total documentada: 22,027 m y diámetro exterior 3,828 m. Para hacer visibles los apoyos se adopta provisionalmente una altura de apoyo de 0,60 m; envolvente cilíndrica desde Z = 0,60 hasta 22,027 m.","partCount":5,"source":{"documentId":"EQ-IMPLANTACION-20260430","title":"Plano del fabricante: implantación de equipos","sheet":"LHD2609-GD01000 · espacio modelo","date":"2026-04-30"},"heightSource":{"documentId":"EQ-CARGAS-20260825","title":"Plano del fabricante: cargas de equipos","sheet":"Espacio modelo","date":"2026-08-25"},"unconfirmedDimensions":["Altura de apoyo de 0,60 m no acotada: hipótesis gráfica.","La planta de los apoyos no confirma su sección ni su construcción a lo largo de la altura.","Geometría de fondos curvos, faldón, soldaduras y espesores sin definir. No se inventan casquetes."],"quantityUse":"Magnitudes de la geometría representada; no son cantidades de material, obra, compra, capacidad útil ni fabricación. En geometrías compuestas se suman superficies y volúmenes de partes y pueden existir solapes no depurados.","partsAreBOM":false} | outer_vessel_envelope | {"min":[42.091258,29.551281,1.6],"max":[45.919195,33.379219,23.627]} | {"boundingBoxM":{"min":[42.091258,29.551281,1.6],"max":[45.919195,33.379219,23.627]},"extentsM":[3.8279369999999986,3.8279379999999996,22.026999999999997],"meshSurfaceM2":288.3822071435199,"meshVolumeM3":247.2829421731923,"closedSolid":true,"windingConsistent":true,"basis":"Submalla exacta de los triángulos del modelo IFC coordinado; separación de componentes sin transformación ni retesselación."} | ["Altura de apoyo de 0,60 m no acotada: hipótesis gráfica.","La planta de los apoyos no confirma su sección ni su construcción a lo largo de la altura.","Geometría de fondos curvos, faldón, soldaduras y espesores sin definir. No se inventan casquetes.","La separación gráfica no aporta cotas de fabricación ni identifica piezas internas no documentadas.","Los materiales y acabados permanecen provisionales; las fotografías públicas solo orientan la apariencia."] | {"id":"SV1801B","sourcePartId":"SV1801B--body","name":"Envolvente cilíndrica del depósito","role":"outer_vessel_envelope","classificationStatus":"provisional","classificationBasis":"Rol del subvolumen gráfico según el activo de detalle; identidad de fabricación no confirmada.","parentEquipmentId":"SV1801B","parentEquipmentGuid":"206t194YPQWO6Wa6jSddOs","isAssemblyIdentityCarrier":true,"sourceFaceRange":[0,764],"sourceCurrentFaceIndices":[0,1,2,3,4,5,6,7,8,9,10,11,12,13,14,15,16,17,18,19,20,21,22,23,24,25,26,27,28,29,30,31,32,33,34,35,36,37,38,39,40,41,42,43,44,45,46,47,48,49,50,51,52,53,54,55,56,57,58,59,60,61,62,63,64,65,66,67,68,69,70,71,72,73,74,75,76,77,78,79,80,81,82,83,84,85,86,87,88,89,90,91,92,93,94,95,96,97,98,99,100,101,102,103,104,105,106,107,108,109,110,111,112,113,114,115,116,117,118,119,120,121,122,123,124,125,126,127,128,129,130,131,132,133,134,135,136,137,138,139,140,141,142,143,144,145,146,147,148,149,150,151,152,153,154,155,156,157,158,159,160,161,162,163,164,165,166,167,168,169,170,171,172,173,174,175,176,177,178,179,180,181,182,183,184,185,186,187,188,189,190,191,192,193,194,195,196,197,198,199,200,201,202,203,204,205,206,207,208,209,210,211,212,213,214,215,216,217,218,219,220,221,222,223,224,225,226,227,228,229,230,231,232,233,234,235,236,237,238,239,240,241,242,243,244,245,246,247,248,249,250,251,252,253,254,255,256,257,258,259,260,261,262,263,264,265,266,267,268,269,270,271,272,273,274,275,276,277,278,279,280,281,282,283,284,285,286,287,288,289,290,291,292,293,294,295,296,297,298,299,300,301,302,303,304,305,306,307,308,309,310,311,312,313,314,315,316,317,318,319,320,321,322,323,324,325,326,327,328,329,330,331,332,333,334,335,336,337,338,339,340,341,342,343,344,345,346,347,348,349,350,351,352,353,354,355,356,357,358,359,360,361,362,363,364,365,366,367,368,369,370,371,372,373,374,375,376,377,378,379,380,381,382,383,384,385,386,387,388,389,390,391,392,393,394,395,396,397,398,399,400,401,402,403,404,405,406,407,408,409,410,411,412,413,414,415,416,417,418,419,420,421,422,423,424,425,426,427,428,429,430,431,432,433,434,435,436,437,438,439,440,441,442,443,444,445,446,447,448,449,450,451,452,453,454,455,456,457,458,459,460,461,462,463,464,465,466,467,468,469,470,471,472,473,474,475,476,477,478,479,480,481,482,483,484,485,486,487,488,489,490,491,492,493,494,495,496,497,498,499,500,501,502,503,504,505,506,507,508,509,510,511,512,513,514,515,516,517,518,519,520,521,522,523,524,525,526,527,528,529,530,531,532,533,534,535,536,537,538,539,540,541,542,543,544,545,546,547,548,549,550,551,552,553,554,555,556,557,558,559,560,561,562,563,564,565,566,567,568,569,570,571,572,573,574,575,576,577,578,579,580,581,582,583,584,585,586,587,588,589,590,591,592,593,594,595,596,597,598,599,600,601,602,603,604,605,606,607,608,609,610,611,612,613,614,615,616,617,618,619,620,621,622,623,624,625,626,627,628,629,630,631,632,633,634,635,636,637,638,639,640,641,642,643,644,645,646,647,648,649,650,651,652,653,654,655,656,657,658,659,660,661,662,663,664,665,666,667,668,669,670,671,672,673,674,675,676,677,678,679,680,681,682,683,684,685,686,687,688,689,690,691,692,693,694,695,696,697,698,699,700,701,702,703,704,705,706,707,708,709,710,711,712,713,714,715,716,717,718,719,720,721,722,723,724,725,726,727,728,729,730,731,732,733,734,735,736,737,738,739,740,741,742,743,744,745,746,747,748,749,750,751,752,753,754,755,756,757,758,759,760,761,762,763],"sourceMeshSha256":"7b60c904c9d84d22fded9be34af09a09a9c198ec8e75e61902634d5e4064c761","sourceVertexIndices":[0,1,2,3,4,5,6,7,8,9,10,11,12,13,14,15,16,17,18,19,20,21,22,23,24,25,26,27,28,29,30,31,32,33,34,35,36,37,38,39,40,41,42,43,44,45,46,47,48,49,50,51,52,53,54,55,56,57,58,59,60,61,62,63,64,65,66,67,68,69,70,71,72,73,74,75,76,77,78,79,80,81,82,83,84,85,86,87,88,89,90,91,92,93,94,95,96,97,98,99,100,101,102,103,104,105,106,107,108,109,110,111,112,113,114,115,116,117,118,119,120,121,122,123,124,125,126,127,128,129,130,131,132,133,134,135,136,137,138,139,140,141,142,143,144,145,146,147,148,149,150,151,152,153,154,155,156,157,158,159,160,161,162,163,164,165,166,167,168,169,170,171,172,173,174,175,176,177,178,179,180,181,182,183,184,185,186,187,188,189,190,191,192,193,194,195,196,197,198,199,200,201,202,203,204,205,206,207,208,209,210,211,212,213,214,215,216,217,218,219,220,221,222,223,224,225,226,227,228,229,230,231,232,233,234,235,236,237,238,239,240,241,242,243,244,245,246,247,248,249,250,251,252,253,254,255,256,257,258,259,260,261,262,263,264,265,266,267,268,269,270,271,272,273,274,275,276,277,278,279,280,281,282,283,284,285,286,287,288,289,290,291,292,293,294,295,296,297,298,299,300,301,302,303,304,305,306,307,308,309,310,311,312,313,314,315,316,317,318,319,320,321,322,323,324,325,326,327,328,329,330,331,332,333,334,335,336,337,338,339,340,341,342,343,344,345,346,347,348,349,350,351,352,353,354,355,356,357,358,359,360,361,362,363,364,365,366,367,368,369,370,371,372,373,374,375,376,377,378,379,380,381,382,383],"separationMethod":"Partición exacta de triángulos existentes; coordenadas y orientación de caras conservadas.","quantityUse":"Magnitudes geométricas del subvolumen; no son cantidades netas de material, fabricación, suministro o capacidad."} | {"id":"SV1801B","name":"Depósito de nitrógeno líquido SV1801B","relationship":"identity_carrier_with_child_components","parentShapeMeaning":"La forma del objeto que conserva el ID del equipo es únicamente su componente principal; el conjunto completo requiere sus hijos."} | {"kind":"assembly_documentation","parentEquipmentId":"SV1801B","directAnchorageVerified":false,"note":"La relación del conjunto con cimentaciones se conserva en el objeto que mantiene el ID del equipo; no se atribuye fijación directa a cada subcomponente."} | Documento de implantación y apoyo del conjunto padre; no acredita fijación individual de este componente. | ["SV1801B","SV1801B--support-01","SV1801B--support-02","SV1801B--support-03","SV1801B--support-04"] | ["SV1801B--support-01","SV1801B--support-02","SV1801B--support-03","SV1801B--support-04"] | ["SV1801B--body","SV1801B--support-01","SV1801B--support-02","SV1801B--support-03","SV1801B--support-04"] | {"Referencia en el plano del fabricante":"7","Identificador del fabricante o del modelo":"SV1801B","Documento de origen":"Plano del fabricante: cargas de equipos · 2026-08-25 · Espacio modelo; número de plano no identificado","Documento CAD derivado":"Conversión DXF del plano de cargas de equipos · 2026-08-25 · espacio modelo","Capa CAD de referencia":"Anotaciones y contornos de equipos","Identificadores CAD del contorno (handles)":"438","Identificador CAD de la cota de altura (handle)":"273B","Cota de altura del fabricante (traducción)":"Altura del equipo: 22.027m","Altura (m)":22.027,"Origen de las dimensiones":"Plano de cargas del fabricante de 2026-08-25: lectura directa del contorno CAD cerrado y de la cota de altura del equipo.","Grado de definición":"Planta derivada del CAD, altura total documentada y alturas parciales provisionales.","Alcance de la geometría":"Geometría compuesta con perfiles CAD y distribución vertical provisional; véase Detalle geométrico.","Origen de la posición":"Punto de referencia del fabricante: entidad CIRCLE, handle 98, en la esquina inferior izquierda de la zona de equipos. Los ejes X e Y son locales y se giran para su implantación UTM.","Hipótesis de modelado":"Nivel de apoyo relativo documentado. Se adopta el cero de proceso a 286,10 m solo para visualización; la equivalencia absoluta no está confirmada. No se añade un espesor de montaje sin cota del fabricante.","Observaciones":"No se dispone de la geometría de los fondos curvos superior e inferior: se utiliza una envolvente cilíndrica de altura total. El radio del eje de referencia, 1 620 mm, y el de la cimentación, 2 400 mm, no son el radio exterior adoptado. Carga variable indicada: 121 500 kg.","Masa propia indicada (kg)":49100,"Diámetro (m)":3.828,"Carga variable indicada por el fabricante (kg)":121500,"Dimensiones de la plataforma de equipos (m)":"27 × 57 m; dimensiones acotadas en el plano general.","Implantación de la plataforma de equipos":"El punto de referencia del fabricante coincide con la esquina suroeste de la zona de equipos. Giro local de −7,82824° para la implantación en coordenadas UTM.","Estado de la cota de instalación":"Nivel de apoyo relativo documentado. Se adopta el cero de proceso a 286,10 m solo para visualización; la equivalencia absoluta no está confirmada. No se añade un espesor de montaje sin cota del fabricante.","Convención de coordenadas":"Coordenadas locales del proyecto en metros. Añadir (729400, 4301550, 285) para recuperar las coordenadas UTM y las cotas del plano.","Identificador del objeto":"SV1801B","Disciplina":"Equipos","Clase IFC":"IfcTank","Fase del modelo":"Revisión de la zona de separación de aire · septiembre de 2026","Representación geométrica IFC":"Sólido IFC4 mediante malla triangular cerrada","Aplicabilidad a mediciones":"Magnitudes de la geometría representada; no son cantidades de material, obra, compra, capacidad útil ni fabricación. En geometrías compuestas se suman superficies y volúmenes de partes y pueden existir solapes no depurados.","Material":"No especificado","Estado de la información":"provisional","Detalle geométrico":"derivado","Incidencias del detalle":["Nivel de apoyo relativo documentado. Se adopta el cero de proceso a 286,10 m solo para visualización; la equivalencia absoluta no está confirmada. No se añade un espesor de montaje sin cota del fabricante.","Cilindro envolvente de altura total; no se dispone de la forma de los fondos, espesores ni componentes internos. El volumen geométrico no es capacidad útil.","Altura de apoyo de 0,60 m no acotada: hipótesis gráfica.","La planta de los apoyos no confirma su sección ni su construcción a lo largo de la altura.","Geometría de fondos curvos, faldón, soldaduras y espesores sin definir. No se inventan casquetes."],"Extensión X del conjunto refinado en ejes del fabricante (m)":3.828000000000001,"Extensión Y del conjunto refinado en ejes del fabricante (m)":3.8279999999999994,"Nivel relativo de apoyo documentado (m)":0.5,"Fuente del nivel de apoyo":{"documentId":"LHD2609-JG00100-20260904","title":"Cimentaciones y pedestales de equipos · revisión recibida 04/09/2026","date":"2026-09-04","sheet":"7 / 7-7","sourceHandles":["1FEDA","1FF68"]},"Criterio de instalación":"Nivel de apoyo relativo documentado. Se adopta el cero de proceso a 286,10 m solo para visualización; la equivalencia absoluta no está confirmada. No se añade un espesor de montaje sin cota del fabricante."} | Subvolumen --body explícitamente identificado en el activo de detalle. | {"receivedDate":"2026-09-08","referenceIds":["jinhong-official-asu","xinrui-jinhong-vaporizers","foto-usuario-20260908-01","foto-usuario-20260908-02","foto-usuario-20260908-04","foto-usuario-20260908-06"],"use":"Color, brillo y lectura de superficies. Sin cambios de geometría o dimensiones.","geometryConfirmedByPhotos":false} | 7 | Conversión DXF del plano de cargas de equipos · 2026-08-25 · espacio modelo | Anotaciones y contornos de equipos | 438 | 273B | Altura del equipo: 22.027m | Plano de cargas del fabricante de 2026-08-25: lectura directa del contorno CAD cerrado y de la cota de altura del equipo. | Planta derivada del CAD, altura total documentada y alturas parciales provisionales. | Geometría compuesta con perfiles CAD y distribución vertical provisional; véase Detalle geométrico. | Punto de referencia del fabricante: entidad CIRCLE, handle 98, en la esquina inferior izquierda de la zona de equipos. Los ejes X e Y son locales y se giran para su implantación UTM. | Nivel de apoyo relativo documentado. Se adopta el cero de proceso a 286,10 m solo para visualización; la equivalencia absoluta no está confirmada. No se añade un espesor de montaje sin cota del fabricante. | No se dispone de la geometría de los fondos curvos superior e inferior: se utiliza una envolvente cilíndrica de altura total. El radio del eje de referencia, 1 620 mm, y el de la cimentación, 2 400 mm, no son el radio exterior adoptado. Carga variable indicada: 121 500 kg. | 49100 | 121500 | 27 × 57 m; dimensiones acotadas en el plano general. | El punto de referencia del fabricante coincide con la esquina suroeste de la zona de equipos. Giro local de −7,82824° para la implantación en coordenadas UTM. | Coordenadas locales del proyecto en metros. Añadir (729400, 4301550, 285) para recuperar las coordenadas UTM y las cotas del plano. | derivado | ["Nivel de apoyo relativo documentado. Se adopta el cero de proceso a 286,10 m solo para visualización; la equivalencia absoluta no está confirmada. No se añade un espesor de montaje sin cota del fabricante.","Cilindro envolvente de altura total; no se dispone de la forma de los fondos, espesores ni componentes internos. El volumen geométrico no es capacidad útil.","Altura de apoyo de 0,60 m no acotada: hipótesis gráfica.","La planta de los apoyos no confirma su sección ni su construcción a lo largo de la altura.","Geometría de fondos curvos, faldón, soldaduras y espesores sin definir. No se inventan casquetes."] | 3.828 | 0.5 | Envolvente cilíndrica del depósito | Envolventes de equipos | unknown | equipment_white_tank | {"documentId":"EQ-CARGAS-20260825","title":"Plano del fabricante: cargas de equipos","sheet":"Espacio modelo","date":"2026-08-25","componentSourceHandles":["438","273B"]} | Submalla de triángulos existentes; no hay nueva posición ni nuevas caras. | Cotas globales del conjunto conservadas aparte; las dimensiones de esta ficha son de la submalla. | Coordinación del conjunto padre; anclaje directo individual no acreditado. | Superficie y volumen geométricos brutos; no constituyen cantidades netas de obra, material o fabricación. | Plano general y dimensiones globales de SV1801B; no se asignan esas dimensiones globales a este componente. | {"documentId":"EQ-CARGAS-20260825","title":"Plano del fabricante: cargas de equipos","sheet":"Espacio modelo","date":"2026-08-25"} | Detalle en planta de 2026-04-30 coordinado de forma preliminar con envolventes y alturas de 2026-08-25 | Altura total documentada: 22,027 m y diámetro exterior 3,828 m. Para hacer visibles los apoyos se adopta provisionalmente una altura de apoyo de 0,60 m; envolvente cilíndrica desde Z = 0,60 hasta 22,027 m. | Submalla exacta; interpretación funcional y cotas parciales provisionales. | ["Altura de apoyo de 0,60 m no acotada: hipótesis gráfica.","La planta de los apoyos no confirma su sección ni su construcción a lo largo de la altura.","Geometría de fondos curvos, faldón, soldaduras y espesores sin definir. No se inventan casquetes."] | [] | No especificado | Magnitudes de la geometría representada; no son cantidades de material, obra, compra, capacidad útil ni fabricación. En geometrías compuestas se suman superficies y volúmenes de partes y pueden existir solapes no depurados. | no | 85232 | 1 | [{"partId":"SV1801B--body","sourceHandles":["438","273B"]},{"partId":"SV1801B--support-01","sourceHandles":["69AB8"]},{"partId":"SV1801B--support-02","sourceHandles":["69ABD"]},{"partId":"SV1801B--support-03","sourceHandles":["69AC2"]},{"partId":"SV1801B--support-04","sourceHandles":["69AC7"]}] | [3.828,3.828,22.027] | SV1801B--body | ["438","273B"] | ["jinhong-official-asu","xinrui-jinhong-vaporizers","foto-usuario-20260908-01","foto-usuario-20260908-02","foto-usuario-20260908-04","foto-usuario-20260908-06"] | 2026-09-08

# IfcUnitaryEquipment: Envolvente de equipo (3)
In: Parcela industrial Jinhong
Description: Envolvente de equipo; PredefinedType: USERDEFINED; Document: Plano del fabricante: cargas de equipos; Cimentaciones de equipos y pedestales del fabricante · revisión recibida 04/09/2026; Group: Equipos; Zona de separación de aire; BIM · Equipos
JH_DimensionesDelModelo - Extensión de la malla en X: 3.81162 m; Extensión de la malla en Y: 2.27356 m; Extensión de la malla en Z: 2.3 m; Cota inferior de visualización: 286.3 m; Cota superior de visualización: 288.6 m
JH_MagnitudesGeometricas - ExtensionX: 3.81162 m; ExtensionY: 2.27356 m; ExtensionZ: 2.3 m; SuperficieDeLaMalla: 37.8 m2; VolumenGeometrico: 14.904 m3
JH_CoordinacionCimentaciones - Relacion: Correspondencia documental; no verifica anclajes ni cotas de montaje.
JH_InformacionBIM - buildingId: process_plant; buildingName: Planta de proceso; level: Apoyo relativo +0.200 m; cero absoluto provisional; category: Envolvente de equipo; ifcClass: IfcUnitaryEquipment; material: {"name":"No especificado","source":"Sin especificación de material en la documentación revisada","status":"unknown"}; source: {"documentId":"EQ-CARGAS-20260825","title":"Plano del fabricante: cargas de equipos","sheet":"Espacio modelo; número de plano no identificado","date":"2026-08-25"}; status: provisional; positioning: {"Estado de la planta":"Derivado del CAD y del giro de implantación","Nivel relativo del apoyo (m)":0.2,"Estado del nivel relativo":"Documentado en el plano de cimentaciones","Cero absoluto de visualización (m)":286.1,"Estado del cero absoluto":"Provisional","Cota del apoyo de visualización (m)":286.3,"Desplazamiento aplicado a la malla (m)":0.2000000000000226,"Criterio":"Nivel de apoyo relativo documentado. Se adopta el cero de proceso a 286,10 m solo para visualización; la equivalencia absoluta no está confirmada. No se añade un espesor de montaje sin cota del fabricante."}; issues: ["La altura de 2,3 m está indicada como aproximada por el fabricante.","Cota inferior contradictoria: -3,000 en etiqueta 28CEA frente a 200 + 1000 = 1200 mm en cadena de cotas; el nivel superior +0,200 es coincidente.","El cero absoluto de la revisión no está definido; 286,10 m sigue siendo una hipótesis de coordinación.","Se alinea el punto inferior del conjunto del equipo, incluidos los pies ya representados, con la superficie de apoyo terminada; no se añade un espesor de calzos, placa o grout del fabricante no documentado."]; ifcAssociations: {"material":false,"document":true,"quantities":true,"containerGuid":"17utmjd_LKsAVvPyuSUhFt","containerName":"Parcela industrial Jinhong"}; installationSource: {"documentId":"LHD2609-JG00100-20260904","title":"Cimentaciones y pedestales de equipos · revisión recibida 04/09/2026","date":"2026-09-04","sheet":"2 / 2-2","sourceHandles":["28CBD","28CE6"]}; representationKind: equipment; visualLayer: {"id":"equipment","name":"Equipos"}; materialAppearance: {"profileId":"equipment_light_gray","name":"Equipo · gris claro provisional","materialName":"No especificado","physicalMaterialStatus":"unknown","physicalMaterialSource":"Sin especificación de material en la documentación revisada","appearanceStatus":"provisional","appearanceBasis":"Referencia visual de fotografías públicas de Jinhong Gas / fabricante. Apariencia provisional para coordinación; fotografías oficiales pueden orientar el color, pero no acreditan el material, el acabado ni el equipo concreto.","note":"La apariencia gráfica no modifica ni confirma la especificación física del material."}; componentSeparation: {"status":"envolvente_del_equipo_sin_interiores","note":"La malla representa el equipo completo o su envolvente. No existe una carcasa separada de los componentes internos."}; classification: {"layerId":"equipment","layerName":"Equipos","role":"Envolvente de equipo","basis":"Clasificación por función del elemento; no modifica las especificaciones documentales."}; layerId: equipment; appearance: {"profileId":"equipment_light_gray","name":"Equipo · gris claro provisional","status":"provisional","basis":"Referencia visual de fotografías públicas de Jinhong Gas / fabricante. Apariencia provisional para coordinación; fotografías oficiales pueden orientar el color, pero no acreditan el material, el acabado ni el equipo concreto.","physicalMaterialUnchanged":true}
JH_Trazabilidad - Referencia en el plano del fabricante: 2; Documento de origen: Plano del fabricante: cargas de equipos · 2026-08-25 · Espacio modelo; número de plano no identificado; Documento CAD derivado: Conversión DXF del plano de cargas de equipos · 2026-08-25 · espacio modelo; Capa CAD de referencia: Anotaciones y contornos de equipos; Cota de altura del fabricante (traducción): Altura del equipo: ≈2.3m; Altura (m): 2.3; Origen de las dimensiones: Plano de cargas del fabricante de 2026-08-25: lectura directa del contorno CAD cerrado y de la cota de altura del equipo.; Grado de definición: Contorno identificado y altura aproximada de 2,3 m indicada por el fabricante.; Alcance de la geometría: Envolvente exterior del equipo; sin detalle constructivo interno.; Origen de la posición: Punto de referencia del fabricante: entidad CIRCLE, handle 98, en la esquina inferior izquierda de la zona de equipos. Los ejes X e Y son locales y se giran para su implantación UTM.; Hipótesis de modelado: Nivel de apoyo relativo documentado. Se adopta el cero de proceso a 286,10 m solo para visualización; la equivalencia absoluta no está confirmada. No se añade un espesor de montaje sin cota del fabricante.; Masa propia indicada (kg): 5000; Dimensión X local (m): 3.6; Dimensión Y local (m): 1.8; Dimensiones de la plataforma de equipos (m): 27 × 57 m; dimensiones acotadas en el plano general.; Implantación de la plataforma de equipos: El punto de referencia del fabricante coincide con la esquina suroeste de la zona de equipos. Giro local de −7,82824° para la implantación en coordenadas UTM.; Estado de la cota de instalación: Nivel de apoyo relativo documentado. Se adopta el cero de proceso a 286,10 m solo para visualización; la equivalencia absoluta no está confirmada. No se añade un espesor de montaje sin cota del fabricante.; Convención de coordenadas: Coordenadas locales del proyecto en metros. Añadir (729400, 4301550, 285) para recuperar las coordenadas UTM y las cotas del plano.; Disciplina: Equipos; Clase IFC: IfcUnitaryEquipment; Fase del modelo: Revisión de la zona de separación de aire · septiembre de 2026; Representación geométrica IFC: Sólido IFC4 mediante malla triangular cerrada; Aplicabilidad a mediciones: Los equipos se representan mediante envolventes. Los espesores y alturas supuestos y el volumen de las envolventes no representan cantidades de materiales, compras, construcción o fabricación.; Material: No especificado; Estado de la información: provisional; Nivel relativo de apoyo documentado (m): 0.2; Fuente del nivel de apoyo: {"documentId":"LHD2609-JG00100-20260904","title":"Cimentaciones y pedestales de equipos · revisión recibida 04/09/2026","date":"2026-09-04","sheet":"2 / 2-2","sourceHandles":["28CBD","28CE6"]}; Criterio de instalación: Nivel de apoyo relativo documentado. Se adopta el cero de proceso a 286,10 m solo para visualización; la equivalencia absoluta no está confirmada. No se añade un espesor de montaje sin cota del fabricante.; Capa BIM: Equipos; Acabado de visualización: Equipo · gris claro provisional; Estado del acabado: provisional; Categoria: Envolvente de equipo; ClaseIFC: IfcUnitaryEquipment; EstadoDeInformacion: provisional; DocumentoFuente: {"documentId":"EQ-CARGAS-20260825","title":"Plano del fabricante: cargas de equipos","sheet":"Espacio modelo; número de plano no identificado","date":"2026-08-25"}; IncidenciasPendientes: ["La altura de 2,3 m está indicada como aproximada por el fabricante.","Cota inferior contradictoria: -3,000 en etiqueta 28CEA frente a 200 + 1000 = 1200 mm en cadena de cotas; el nivel superior +0,200 es coincidente.","El cero absoluto de la revisión no está definido; 286,10 m sigue siendo una hipótesis de coordinación.","Se alinea el punto inferior del conjunto del equipo, incluidos los pies ya representados, con la superficie de apoyo terminada; no se añade un espesor de calzos, placa o grout del fabricante no documentado."]; UsoDeLasMagnitudes: Geometría de coordinación. Los volúmenes de referencia y subcomponentes no son cantidades de material ni componentes de fabricación certificados.
JH_CriterioDePosicion - PosicionYEstado: {"Estado de la planta":"Derivado del CAD y del giro de implantación","Nivel relativo del apoyo (m)":0.2,"Estado del nivel relativo":"Documentado en el plano de cimentaciones","Cero absoluto de visualización (m)":286.1,"Estado del cero absoluto":"Provisional","Cota del apoyo de visualización (m)":286.3,"Desplazamiento aplicado a la malla (m)":0.2000000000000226,"Criterio":"Nivel de apoyo relativo documentado. Se adopta el cero de proceso a 286,10 m solo para visualización; la equivalencia absoluta no está confirmada. No se añade un espesor de montaje sin cota del fabricante."}
JH_EvidenciaDeMaterial - name: No especificado; source: Sin especificación de material en la documentación revisada; status: unknown
JH_DimensionesDocumentadas - Dimensión X local del contorno CAD: 3.6 m; Dimensión Y local del contorno CAD: 1.8 m; Altura acotada aproximada: 2.3 m; Cota relativa de la superficie de apoyo: 0.2 m
JH_CapaBIM - IdentificadorCapa: equipment; NombreCapa: Equipos; Funcion: Envolvente de equipo; VisibilidadInicial: yes
JH_AcabadoVisual - Perfil: equipment_light_gray; Acabado: Equipo · gris claro provisional; ColorRGB: [0.88,0.89,0.88]; Rugosidad: 0.45; Metallicidad: 0.28; Estado: provisional; Referencia: Referencia visual de fotografías públicas de Jinhong Gas / fabricante. Apariencia provisional para coordinación; fotografías oficiales pueden orientar el color, pero no acreditan el material, el acabado ni el equipo concreto.; Nota: La apariencia no certifica el material físico ni el acabado de fabricación.
Name | ElementosDeCimentacion = foundationIds | dimensions | geometryMetrics | visualizationIdentity | Identificador del fabricante o del modelo = Identificador del objeto = Identificador | Identificadores CAD del contorno (handles) | Identificador CAD de la cota de altura (handle)
Secador frigorífico de aire comprimido RU1101A | ["found_0904_5678683977aad3","found_0904_0f2bad74c83724","found_0904_1c12b72639217c"] | {"documented":[{"label":"Dimensión X local del contorno CAD","value":3.6,"unit":"m","source":"EQ-CARGAS-20260825 · contorno CAD · handles 3FF","status":"derivado"},{"label":"Dimensión Y local del contorno CAD","value":1.8,"unit":"m","source":"EQ-CARGAS-20260825 · contorno CAD · handles 3FF","status":"derivado"},{"label":"Altura acotada aproximada","value":2.3,"unit":"m","source":"EQ-CARGAS-20260825 · handle 404","status":"documentado"},{"label":"Cota relativa de la superficie de apoyo","value":0.2,"unit":"m","source":"LHD2609-JG00100-20260904 · sección 2 / 2-2 · 28CBD, 28CE6","status":"documentado"}],"geometry":[{"label":"Extensión de la malla en X","value":3.811618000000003,"unit":"m","source":"Geometría releída del IFC; datum absoluto de proceso provisional","status":"derivado"},{"label":"Extensión de la malla en Y","value":2.273559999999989,"unit":"m","source":"Geometría releída del IFC; datum absoluto de proceso provisional","status":"derivado"},{"label":"Extensión de la malla en Z","value":2.3,"unit":"m","source":"Geometría releída del IFC; datum absoluto de proceso provisional","status":"derivado"},{"label":"Cota inferior de visualización","value":286.3,"unit":"m","source":"Geometría releída del IFC; datum absoluto de proceso provisional","status":"derivado"},{"label":"Cota superior de visualización","value":288.6,"unit":"m","source":"Geometría releída del IFC; datum absoluto de proceso provisional","status":"derivado"}],"notes":["Las extensiones de la malla se miden en los ejes del proyecto tras el giro de implantación; no sustituyen las dimensiones locales del fabricante.","La envolvente, su volumen y los espesores de visualización no son volúmenes de material ni cantidades de compra, construcción o fabricación.","Las dimensiones documentadas distinguen cotas explícitas y medidas extraídas de contornos CAD; las dimensiones geométricas describen únicamente la malla publicada."]} | {"boundingBoxM":{"min":[47.239312,64.042584,1.3],"max":[51.05093,66.316144,3.6]},"extentsM":[3.811618,2.27356,2.3],"meshSurfaceM2":37.800006,"meshVolumeM3":14.904004,"closedSolid":true,"basis":"Magnitudes de las mallas representadas, no cantidades certificadas de obra, compra o fabricación. Las partes pueden compartir superficies; no se suman como un despiece de materiales."} | {"elementId":"RU1101A","ifcGuid":"2GU3eAOmzIvxMNo8Z8yNcX","ifcClass":"IfcUnitaryEquipment","buildingId":"process_plant","buildingName":"Planta de proceso","sourceDocumentId":"EQ-CARGAS-20260825","sourceRepresentationKind":"equipment"} | RU1101A | 3FF | 404
Secador frigorífico de aire comprimido RU1101B | ["found_0904_6c005dd8549efe","found_0904_8eb17fb9bfce5d","found_0904_f4a89c716abc6c"] | {"documented":[{"label":"Dimensión X local del contorno CAD","value":3.6,"unit":"m","source":"EQ-CARGAS-20260825 · contorno CAD · handles 3FC","status":"derivado"},{"label":"Dimensión Y local del contorno CAD","value":1.8,"unit":"m","source":"EQ-CARGAS-20260825 · contorno CAD · handles 3FC","status":"derivado"},{"label":"Altura acotada aproximada","value":2.3,"unit":"m","source":"EQ-CARGAS-20260825 · handle 25E3","status":"documentado"},{"label":"Cota relativa de la superficie de apoyo","value":0.2,"unit":"m","source":"LHD2609-JG00100-20260904 · sección 2 / 2-2 · 28CBD, 28CE6","status":"documentado"}],"geometry":[{"label":"Extensión de la malla en X","value":3.8116179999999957,"unit":"m","source":"Geometría releída del IFC; datum absoluto de proceso provisional","status":"derivado"},{"label":"Extensión de la malla en Y","value":2.2735600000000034,"unit":"m","source":"Geometría releída del IFC; datum absoluto de proceso provisional","status":"derivado"},{"label":"Extensión de la malla en Z","value":2.3,"unit":"m","source":"Geometría releída del IFC; datum absoluto de proceso provisional","status":"derivado"},{"label":"Cota inferior de visualización","value":286.3,"unit":"m","source":"Geometría releída del IFC; datum absoluto de proceso provisional","status":"derivado"},{"label":"Cota superior de visualización","value":288.6,"unit":"m","source":"Geometría releída del IFC; datum absoluto de proceso provisional","status":"derivado"}],"notes":["Las extensiones de la malla se miden en los ejes del proyecto tras el giro de implantación; no sustituyen las dimensiones locales del fabricante.","La envolvente, su volumen y los espesores de visualización no son volúmenes de material ni cantidades de compra, construcción o fabricación.","Las dimensiones documentadas distinguen cotas explícitas y medidas extraídas de contornos CAD; las dimensiones geométricas describen únicamente la malla publicada."]} | {"boundingBoxM":{"min":[53.579669,63.170879,1.3],"max":[57.391287,65.444439,3.6]},"extentsM":[3.811618,2.27356,2.3],"meshSurfaceM2":37.800006,"meshVolumeM3":14.904004,"closedSolid":true,"basis":"Magnitudes de las mallas representadas, no cantidades certificadas de obra, compra o fabricación. Las partes pueden compartir superficies; no se suman como un despiece de materiales."} | {"elementId":"RU1101B","ifcGuid":"3BsEW02cjQCQjSIlDnhqK6","ifcClass":"IfcUnitaryEquipment","buildingId":"process_plant","buildingName":"Planta de proceso","sourceDocumentId":"EQ-CARGAS-20260825","sourceRepresentationKind":"equipment"} | RU1101B | 3FC | 25E3
Secador frigorífico de aire comprimido RU1101C | ["found_0904_57e3a3d649e27e","found_0904_9aabf738deda63","found_0904_472a35ad377965"] | {"documented":[{"label":"Dimensión X local del contorno CAD","value":3.6,"unit":"m","source":"EQ-CARGAS-20260825 · contorno CAD · handles 3F9","status":"derivado"},{"label":"Dimensión Y local del contorno CAD","value":1.8,"unit":"m","source":"EQ-CARGAS-20260825 · contorno CAD · handles 3F9","status":"derivado"},{"label":"Altura acotada aproximada","value":2.3,"unit":"m","source":"EQ-CARGAS-20260825 · handle 25F1","status":"documentado"},{"label":"Cota relativa de la superficie de apoyo","value":0.2,"unit":"m","source":"LHD2609-JG00100-20260904 · sección 2 / 2-2 · 28CBD, 28CE6","status":"documentado"}],"geometry":[{"label":"Extensión de la malla en X","value":3.811618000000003,"unit":"m","source":"Geometría releída del IFC; datum absoluto de proceso provisional","status":"derivado"},{"label":"Extensión de la malla en Y","value":2.2735599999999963,"unit":"m","source":"Geometría releída del IFC; datum absoluto de proceso provisional","status":"derivado"},{"label":"Extensión de la malla en Z","value":2.3,"unit":"m","source":"Geometría releída del IFC; datum absoluto de proceso provisional","status":"derivado"},{"label":"Cota inferior de visualización","value":286.3,"unit":"m","source":"Geometría releída del IFC; datum absoluto de proceso provisional","status":"derivado"},{"label":"Cota superior de visualización","value":288.6,"unit":"m","source":"Geometría releída del IFC; datum absoluto de proceso provisional","status":"derivado"}],"notes":["Las extensiones de la malla se miden en los ejes del proyecto tras el giro de implantación; no sustituyen las dimensiones locales del fabricante.","La envolvente, su volumen y los espesores de visualización no son volúmenes de material ni cantidades de compra, construcción o fabricación.","Las dimensiones documentadas distinguen cotas explícitas y medidas extraídas de contornos CAD; las dimensiones geométricas describen únicamente la malla publicada."]} | {"boundingBoxM":{"min":[59.920026,62.299174,1.3],"max":[63.731644,64.572734,3.6]},"extentsM":[3.811618,2.27356,2.3],"meshSurfaceM2":37.800006,"meshVolumeM3":14.904004,"closedSolid":true,"basis":"Magnitudes de las mallas representadas, no cantidades certificadas de obra, compra o fabricación. Las partes pueden compartir superficies; no se suman como un despiece de materiales."} | {"elementId":"RU1101C","ifcGuid":"0ytXB5l0rSjP0sJmJy$m2l","ifcClass":"IfcUnitaryEquipment","buildingId":"process_plant","buildingName":"Planta de proceso","sourceDocumentId":"EQ-CARGAS-20260825","sourceRepresentationKind":"equipment"} | RU1101C | 3F9 | 25F1

# IfcWall (187)
In: Planta baja
Description: Muro; PredefinedType: STANDARD
JH_InformacionBIM - level: Planta baja; category: Muro; ifcClass: IfcWall; status: derivado; componentSeparation: {"status":"objeto_independiente","note":"Control de visibilidad del objeto completo; la clasificación no altera la malla."}
JH_Trazabilidad - Sistema de coordenadas: Coordenadas de proyecto en metros; sumar (729400, 4301550, 285) para recuperar las coordenadas UTM y cotas de los planos.; Uso del modelo: Reconstrucción tridimensional de la documentación y revisión preliminar de coordinación; pendiente de revisión por el equipo de diseño.; Verificación de la malla: Malla cerrada, orientación coherente de las caras y volumen positivo.; Referencia de implantación: Plano general U004 de 2026-07-31; geometría vectorial del PDF registrada con las coordenadas de lindero indicadas.; Clase IFC: IfcWall; Fase del modelo: V0.1 · Reconstrucción documental y coordinación preliminar; Representación geométrica: Sólido de malla triangular cerrada en IFC4; Aplicabilidad de las mediciones: Volumen exclusivamente geométrico; los espesores de representación, las simplificaciones y las envolventes no constituyen mediciones de compra, ejecución, fabricación ni volumen neto de material.; Estado del acabado: criterio_visual; Categoria: Muro; ClaseIFC: IfcWall; EstadoDeInformacion: derivado; UsoDeLasMagnitudes: Geometría de coordinación. Los volúmenes de referencia y subcomponentes no son cantidades de material ni componentes de fabricación certificados.
JH_EvidenciaDeMaterial - status: known
JH_CapaBIM - Funcion: Muro; VisibilidadInicial: yes
JH_AcabadoVisual - Estado: criterio_visual; Nota: La apariencia no certifica el material físico ni el acabado de fabricación.
Name | Document | Material = JH_Trazabilidad, Material = name | Dimensiones de la caja local del elemento (X, Y, Z) | Cota mínima absoluta de la malla (m) | Cota máxima absoluta de la malla (m) | Volumen geométrico bruto (m3) = Volumen geométrico (m³) | Reference = Identificador del elemento = Identificador | IsExternal | ExtensionX (m) | ExtensionY (m) | ExtensionZ (m) | SuperficieDeLaMalla (m2) | VolumenGeometrico (m3) = GrossVolume (m3) | buildingId | buildingName = Edificio | material | dimensions | JH_InformacionBIM, source = DocumentoFuente | issues = IncidenciasPendientes | positioning = PosicionYEstado | commonProperties | geometryMetrics | ifcAssociations | visualLayer | materialAppearance | visualizationIdentity | classification | layerId = IdentificadorCapa | appearance | Planos de referencia | Base geométrica | Espesor del muro (m) = Espesor del muro (m) | Tratamiento de los huecos | Representación de los acabados | Estado de la implantación | Disciplina | Referencia del material = JH_EvidenciaDeMaterial, source | Cota de planta baja terminada (m) | Capa BIM = NombreCapa | Acabado de visualización = Acabado | Perfil | ColorRGB | Rugosidad | Metallicidad | Referencia | Group | Discrepancia entre versiones
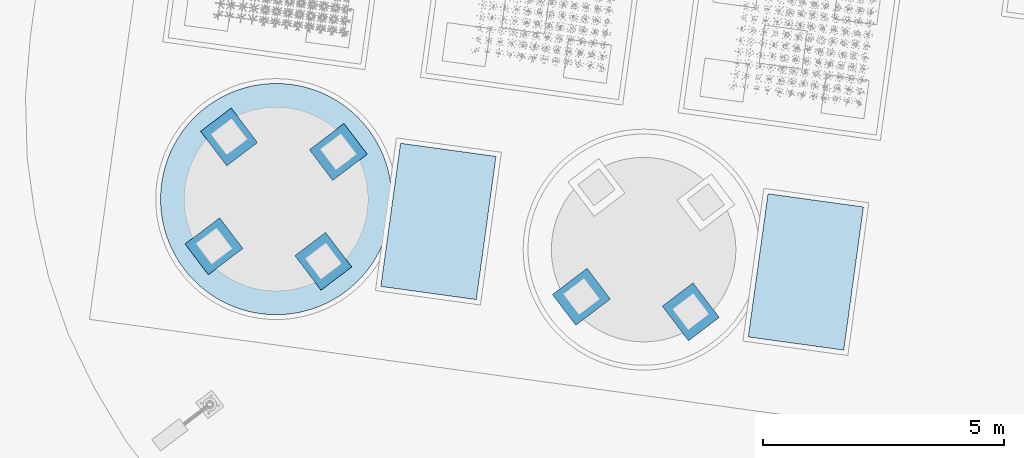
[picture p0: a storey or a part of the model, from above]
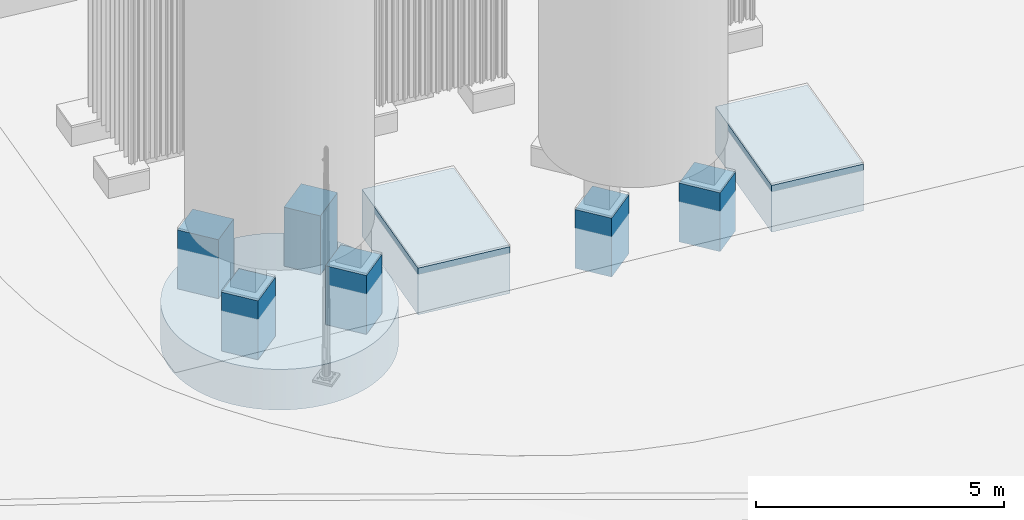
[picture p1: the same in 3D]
Properties of the parts of a building model (IFC4), part 113 of 134

# IfcWall (187)
Name | Document | Material = JH_Trazabilidad, Material = name | Dimensiones de la caja local del elemento (X, Y, Z) | Cota mínima absoluta de la malla (m) | Cota máxima absoluta de la malla (m) | Volumen geométrico bruto (m3) = Volumen geométrico (m³) | Reference = Identificador del elemento = Identificador | IsExternal | ExtensionX (m) | ExtensionY (m) | ExtensionZ (m) | SuperficieDeLaMalla (m2) | VolumenGeometrico (m3) = GrossVolume (m3) | buildingId | buildingName = Edificio | material | dimensions | JH_InformacionBIM, source = DocumentoFuente | issues = IncidenciasPendientes | positioning = PosicionYEstado | commonProperties | geometryMetrics | ifcAssociations | visualLayer | materialAppearance | visualizationIdentity | classification | layerId = IdentificadorCapa | appearance | Planos de referencia | Base geométrica | Espesor del muro (m) = Espesor del muro (m) | Tratamiento de los huecos | Representación de los acabados | Estado de la implantación | Disciplina | Referencia del material = JH_EvidenciaDeMaterial, source | Cota de planta baja terminada (m) | Capa BIM = NombreCapa | Acabado de visualización = Acabado | Perfil | ColorRGB | Rugosidad | Metallicidad | Referencia | Group | Discrepancia entre versiones
Sala de bombas contra incendios · Zócalo de hormigón · eje A · tramo 01 | Planos de arquitectura de la sala de bombas contra incendios; Planos de arquitectura de la sala de bombas contra incendios | Hormigón prefabricado macizo | 2 × 0.2 × 1.2 | 286.25 | 287.45 | 0.48 | pump_house_0002 | yes | 2.0086 | 0.470544 | 1.2 | 6.08 | 0.48 | pump_house | Sala de bombas contra incendios | {"name":"Hormigón prefabricado macizo","source":"ARQ-SB-20260710 · Arquitectura A103 / p. 5; Estructura A201 / p. 4","status":"known"} | {"documented":[{"label":"Espesor del muro","value":0.2,"unit":"m","source":"ARQ-SB-20260710 · Arquitectura A103 / p. 5; Estructura A201 / p. 4","status":"documentado"}],"geometry":[{"label":"Dimensiones de la caja local del elemento (X, Y, Z)","value":"2 × 0.2 × 1.2","unit":"m","source":"Malla triangulada del elemento en ejes locales del edificio","status":"derivado"},{"label":"Cota mínima absoluta de la malla","value":286.25,"unit":"m","source":"Malla de proyecto y origen altimétrico 285 m","status":"derivado"},{"label":"Cota máxima absoluta de la malla","value":287.45,"unit":"m","source":"Malla de proyecto y origen altimétrico 285 m","status":"derivado"},{"label":"Volumen geométrico bruto","value":0.48,"unit":"m³","source":"Malla cerrada del elemento","status":"derivado"}],"notes":["Las dimensiones documentadas proceden de anotaciones o cuadros; la caja y el volumen se calculan a partir de la malla.","El volumen es exclusivamente geométrico y bruto; no representa una medición neta de material ni una cantidad de compra."]} | {"documentId":"ARQ-SB-20260710","title":"Planos de arquitectura de la sala de bombas contra incendios","date":"2026-07-10","sheet":"Arquitectura A103 / p. 5; Estructura A201 / p. 4"} | ["Envolvente exterior controlada por la planta de arquitectura; no se han modelado individualmente todas las capas de acabado.","Registro de líneas del PDF general con envolvente de 10,2 × 8,2 m. Estimación de trabajo de implantación de ±0,15 m, pendiente de CAD nativo; no constituye una precisión topográfica garantizada."] | {"horizontalStatus":"derivado","verticalStatus":"derivado","baseElevationM":286.25,"note":"Registro de líneas del PDF general con envolvente de 10,2 × 8,2 m. Estimación de trabajo de implantación de ±0,15 m, pendiente de CAD nativo; no constituye una precisión topográfica garantizada."} | {"Pset_WallCommon":{"IsExternal":{"value":true,"source":"ARQ-SB-20260710 · A101, A103 y alzados; elemento de la envolvente exterior identificada en planta","status":"known"}}} | {"boundingBoxM":{"min":[8.116092,26.521441,1.25],"max":[10.124694,26.991985,2.45]},"extentsM":[2.008602,0.470544,1.2],"meshSurfaceM2":6.079997,"meshVolumeM3":0.48,"closedSolid":true,"basis":"Geometría triangulada releída del IFC; envolventes y magnitudes no contractuales."} | {"material":true,"document":true,"quantities":true,"containerGuid":"0Wh59pm9LO_einrwiq6Es1","containerName":"Planta baja"} | {"id":"architecture","name":"Arquitectura"} | {"profileId":"concrete_precast","name":"Hormigón prefabricado","materialName":"Hormigón prefabricado macizo","physicalMaterialStatus":"known","physicalMaterialSource":"ARQ-SB-20260710 · Arquitectura A103 / p. 5; Estructura A201 / p. 4","appearanceStatus":"criterio_visual","appearanceBasis":"Interpretación visual del material documental; el acabado, tono y parámetros PBR no son una especificación contractual.","note":"La apariencia gráfica no modifica ni confirma la especificación física del material."} | {"elementId":"pump_house_0002","ifcGuid":"05x0DcxFXTERG6$vCkdgfr","ifcClass":"IfcWall","buildingId":"pump_house","buildingName":"Sala de bombas contra incendios","sourceDocumentId":"ARQ-SB-20260710","sourceRepresentationKind":"documentary_mesh"} | {"layerId":"architecture","layerName":"Arquitectura","role":"Muro","basis":"Clasificación por función del elemento; no modifica las especificaciones documentales."} | architecture | {"profileId":"concrete_precast","name":"Hormigón prefabricado","status":"criterio_visual","basis":"Interpretación visual del material documental; el acabado, tono y parámetros PBR no son una especificación contractual.","physicalMaterialUnchanged":true} | ARQ-SB-20260710 · Arquitectura A103 / p. 5; Estructura A201 / p. 4 | Dimensiones contrastadas con los planos; reconstrucción geométrica a partir de documentación de diseño. | 0.2 | Muros segmentados con huecos reales para puertas y ventanas. | Envolvente exterior controlada por la planta de arquitectura; no se han modelado individualmente todas las capas de acabado. | Registro de líneas del PDF general con envolvente de 10,2 × 8,2 m. Estimación de trabajo de implantación de ±0,15 m, pendiente de CAD nativo; no constituye una precisión topográfica garantizada. | Arquitectura | ARQ-SB-20260710 · Arquitectura A103 / p. 5; Estructura A201 / p. 4 | 286.25 | Arquitectura | Hormigón prefabricado | concrete_precast | [0.756863,0.752941,0.717647] | 0.86 | 0 | Interpretación visual del material documental; el acabado, tono y parámetros PBR no son una especificación contractual. | Arquitectura; BIM · Arquitectura
Sala de bombas contra incendios · Zócalo de hormigón · eje A · tramo 02 | Planos de arquitectura de la sala de bombas contra incendios; Planos de arquitectura de la sala de bombas contra incendios | Hormigón prefabricado macizo | 1.2 × 0.2 × 1.2 | 286.25 | 287.45 | 0.288 | pump_house_0003 | yes | 1.21606 | 0.361581 | 1.2 | 3.84 | 0.288 | pump_house | Sala de bombas contra incendios | {"name":"Hormigón prefabricado macizo","source":"ARQ-SB-20260710 · Arquitectura A103 / p. 5; Estructura A201 / p. 4","status":"known"} | {"documented":[{"label":"Espesor del muro","value":0.2,"unit":"m","source":"ARQ-SB-20260710 · Arquitectura A103 / p. 5; Estructura A201 / p. 4","status":"documentado"}],"geometry":[{"label":"Dimensiones de la caja local del elemento (X, Y, Z)","value":"1.2 × 0.2 × 1.2","unit":"m","source":"Malla triangulada del elemento en ejes locales del edificio","status":"derivado"},{"label":"Cota mínima absoluta de la malla","value":286.25,"unit":"m","source":"Malla de proyecto y origen altimétrico 285 m","status":"derivado"},{"label":"Cota máxima absoluta de la malla","value":287.45,"unit":"m","source":"Malla de proyecto y origen altimétrico 285 m","status":"derivado"},{"label":"Volumen geométrico bruto","value":0.288,"unit":"m³","source":"Malla cerrada del elemento","status":"derivado"}],"notes":["Las dimensiones documentadas proceden de anotaciones o cuadros; la caja y el volumen se calculan a partir de la malla.","El volumen es exclusivamente geométrico y bruto; no representa una medición neta de material ni una cantidad de compra."]} | {"documentId":"ARQ-SB-20260710","title":"Planos de arquitectura de la sala de bombas contra incendios","date":"2026-07-10","sheet":"Arquitectura A103 / p. 5; Estructura A201 / p. 4"} | ["Envolvente exterior controlada por la planta de arquitectura; no se han modelado individualmente todas las capas de acabado.","Registro de líneas del PDF general con envolvente de 10,2 × 8,2 m. Estimación de trabajo de implantación de ±0,15 m, pendiente de CAD nativo; no constituye una precisión topográfica garantizada."] | {"horizontalStatus":"derivado","verticalStatus":"derivado","baseElevationM":286.25,"note":"Registro de líneas del PDF general con envolvente de 10,2 × 8,2 m. Estimación de trabajo de implantación de ±0,15 m, pendiente de CAD nativo; no constituye una precisión topográfica garantizada."} | {"Pset_WallCommon":{"IsExternal":{"value":true,"source":"ARQ-SB-20260710 · A101, A103 y alzados; elemento de la envolvente exterior identificada en planta","status":"known"}}} | {"boundingBoxM":{"min":[10.097453,26.357996,1.25],"max":[11.313511,26.719577,2.45]},"extentsM":[1.216058,0.361581,1.2],"meshSurfaceM2":3.84,"meshVolumeM3":0.288,"closedSolid":true,"basis":"Geometría triangulada releída del IFC; envolventes y magnitudes no contractuales."} | {"material":true,"document":true,"quantities":true,"containerGuid":"0Wh59pm9LO_einrwiq6Es1","containerName":"Planta baja"} | {"id":"architecture","name":"Arquitectura"} | {"profileId":"concrete_precast","name":"Hormigón prefabricado","materialName":"Hormigón prefabricado macizo","physicalMaterialStatus":"known","physicalMaterialSource":"ARQ-SB-20260710 · Arquitectura A103 / p. 5; Estructura A201 / p. 4","appearanceStatus":"criterio_visual","appearanceBasis":"Interpretación visual del material documental; el acabado, tono y parámetros PBR no son una especificación contractual.","note":"La apariencia gráfica no modifica ni confirma la especificación física del material."} | {"elementId":"pump_house_0003","ifcGuid":"3Sv8yIAEjUJ9ojRDyYvqyU","ifcClass":"IfcWall","buildingId":"pump_house","buildingName":"Sala de bombas contra incendios","sourceDocumentId":"ARQ-SB-20260710","sourceRepresentationKind":"documentary_mesh"} | {"layerId":"architecture","layerName":"Arquitectura","role":"Muro","basis":"Clasificación por función del elemento; no modifica las especificaciones documentales."} | architecture | {"profileId":"concrete_precast","name":"Hormigón prefabricado","status":"criterio_visual","basis":"Interpretación visual del material documental; el acabado, tono y parámetros PBR no son una especificación contractual.","physicalMaterialUnchanged":true} | ARQ-SB-20260710 · Arquitectura A103 / p. 5; Estructura A201 / p. 4 | Dimensiones contrastadas con los planos; reconstrucción geométrica a partir de documentación de diseño. | 0.2 | Muros segmentados con huecos reales para puertas y ventanas. | Envolvente exterior controlada por la planta de arquitectura; no se han modelado individualmente todas las capas de acabado. | Registro de líneas del PDF general con envolvente de 10,2 × 8,2 m. Estimación de trabajo de implantación de ±0,15 m, pendiente de CAD nativo; no constituye una precisión topográfica garantizada. | Arquitectura | ARQ-SB-20260710 · Arquitectura A103 / p. 5; Estructura A201 / p. 4 | 286.25 | Arquitectura | Hormigón prefabricado | concrete_precast | [0.756863,0.752941,0.717647] | 0.86 | 0 | Interpretación visual del material documental; el acabado, tono y parámetros PBR no son una especificación contractual. | Arquitectura; BIM · Arquitectura
Sala de bombas contra incendios · Zócalo de hormigón · eje A · tramo 03 | Planos de arquitectura de la sala de bombas contra incendios; Planos de arquitectura de la sala de bombas contra incendios | Hormigón prefabricado macizo | 3.8 × 0.2 × 1.2 | 286.25 | 287.45 | 0.912 | pump_house_0004 | yes | 3.79183 | 0.715711 | 1.2 | 11.12 | 0.911999 | pump_house | Sala de bombas contra incendios | {"name":"Hormigón prefabricado macizo","source":"ARQ-SB-20260710 · Arquitectura A103 / p. 5; Estructura A201 / p. 4","status":"known"} | {"documented":[{"label":"Espesor del muro","value":0.2,"unit":"m","source":"ARQ-SB-20260710 · Arquitectura A103 / p. 5; Estructura A201 / p. 4","status":"documentado"}],"geometry":[{"label":"Dimensiones de la caja local del elemento (X, Y, Z)","value":"3.8 × 0.2 × 1.2","unit":"m","source":"Malla triangulada del elemento en ejes locales del edificio","status":"derivado"},{"label":"Cota mínima absoluta de la malla","value":286.25,"unit":"m","source":"Malla de proyecto y origen altimétrico 285 m","status":"derivado"},{"label":"Cota máxima absoluta de la malla","value":287.45,"unit":"m","source":"Malla de proyecto y origen altimétrico 285 m","status":"derivado"},{"label":"Volumen geométrico bruto","value":0.912,"unit":"m³","source":"Malla cerrada del elemento","status":"derivado"}],"notes":["Las dimensiones documentadas proceden de anotaciones o cuadros; la caja y el volumen se calculan a partir de la malla.","El volumen es exclusivamente geométrico y bruto; no representa una medición neta de material ni una cantidad de compra."]} | {"documentId":"ARQ-SB-20260710","title":"Planos de arquitectura de la sala de bombas contra incendios","date":"2026-07-10","sheet":"Arquitectura A103 / p. 5; Estructura A201 / p. 4"} | ["Envolvente exterior controlada por la planta de arquitectura; no se han modelado individualmente todas las capas de acabado.","Registro de líneas del PDF general con envolvente de 10,2 × 8,2 m. Estimación de trabajo de implantación de ±0,15 m, pendiente de CAD nativo; no constituye una precisión topográfica garantizada."] | {"horizontalStatus":"derivado","verticalStatus":"derivado","baseElevationM":286.25,"note":"Registro de líneas del PDF general con envolvente de 10,2 × 8,2 m. Estimación de trabajo de implantación de ±0,15 m, pendiente de CAD nativo; no constituye una precisión topográfica garantizada."} | {"Pset_WallCommon":{"IsExternal":{"value":true,"source":"ARQ-SB-20260710 · A101, A103 y alzados; elemento de la envolvente exterior identificada en planta","status":"known"}}} | {"boundingBoxM":{"min":[11.28627,25.840421,1.25],"max":[15.078098,26.556132,2.45]},"extentsM":[3.791828,0.715711,1.2],"meshSurfaceM2":11.119998,"meshVolumeM3":0.911999,"closedSolid":true,"basis":"Geometría triangulada releída del IFC; envolventes y magnitudes no contractuales."} | {"material":true,"document":true,"quantities":true,"containerGuid":"0Wh59pm9LO_einrwiq6Es1","containerName":"Planta baja"} | {"id":"architecture","name":"Arquitectura"} | {"profileId":"concrete_precast","name":"Hormigón prefabricado","materialName":"Hormigón prefabricado macizo","physicalMaterialStatus":"known","physicalMaterialSource":"ARQ-SB-20260710 · Arquitectura A103 / p. 5; Estructura A201 / p. 4","appearanceStatus":"criterio_visual","appearanceBasis":"Interpretación visual del material documental; el acabado, tono y parámetros PBR no son una especificación contractual.","note":"La apariencia gráfica no modifica ni confirma la especificación física del material."} | {"elementId":"pump_house_0004","ifcGuid":"1kBFcAzlTGnQXY$Sm4UpxB","ifcClass":"IfcWall","buildingId":"pump_house","buildingName":"Sala de bombas contra incendios","sourceDocumentId":"ARQ-SB-20260710","sourceRepresentationKind":"documentary_mesh"} | {"layerId":"architecture","layerName":"Arquitectura","role":"Muro","basis":"Clasificación por función del elemento; no modifica las especificaciones documentales."} | architecture | {"profileId":"concrete_precast","name":"Hormigón prefabricado","status":"criterio_visual","basis":"Interpretación visual del material documental; el acabado, tono y parámetros PBR no son una especificación contractual.","physicalMaterialUnchanged":true} | ARQ-SB-20260710 · Arquitectura A103 / p. 5; Estructura A201 / p. 4 | Dimensiones contrastadas con los planos; reconstrucción geométrica a partir de documentación de diseño. | 0.2 | Muros segmentados con huecos reales para puertas y ventanas. | Envolvente exterior controlada por la planta de arquitectura; no se han modelado individualmente todas las capas de acabado. | Registro de líneas del PDF general con envolvente de 10,2 × 8,2 m. Estimación de trabajo de implantación de ±0,15 m, pendiente de CAD nativo; no constituye una precisión topográfica garantizada. | Arquitectura | ARQ-SB-20260710 · Arquitectura A103 / p. 5; Estructura A201 / p. 4 | 286.25 | Arquitectura | Hormigón prefabricado | concrete_precast | [0.756863,0.752941,0.717647] | 0.86 | 0 | Interpretación visual del material documental; el acabado, tono y parámetros PBR no son una especificación contractual. | Arquitectura; BIM · Arquitectura
Sala de bombas contra incendios · Zócalo de hormigón · eje A · tramo 04 | Planos de arquitectura de la sala de bombas contra incendios; Planos de arquitectura de la sala de bombas contra incendios | Hormigón prefabricado macizo | 1.2 × 0.2 × 1.2 | 286.25 | 287.45 | 0.288 | pump_house_0005 | yes | 1.21606 | 0.361581 | 1.2 | 3.84 | 0.288001 | pump_house | Sala de bombas contra incendios | {"name":"Hormigón prefabricado macizo","source":"ARQ-SB-20260710 · Arquitectura A103 / p. 5; Estructura A201 / p. 4","status":"known"} | {"documented":[{"label":"Espesor del muro","value":0.2,"unit":"m","source":"ARQ-SB-20260710 · Arquitectura A103 / p. 5; Estructura A201 / p. 4","status":"documentado"}],"geometry":[{"label":"Dimensiones de la caja local del elemento (X, Y, Z)","value":"1.2 × 0.2 × 1.2","unit":"m","source":"Malla triangulada del elemento en ejes locales del edificio","status":"derivado"},{"label":"Cota mínima absoluta de la malla","value":286.25,"unit":"m","source":"Malla de proyecto y origen altimétrico 285 m","status":"derivado"},{"label":"Cota máxima absoluta de la malla","value":287.45,"unit":"m","source":"Malla de proyecto y origen altimétrico 285 m","status":"derivado"},{"label":"Volumen geométrico bruto","value":0.288,"unit":"m³","source":"Malla cerrada del elemento","status":"derivado"}],"notes":["Las dimensiones documentadas proceden de anotaciones o cuadros; la caja y el volumen se calculan a partir de la malla.","El volumen es exclusivamente geométrico y bruto; no representa una medición neta de material ni una cantidad de compra."]} | {"documentId":"ARQ-SB-20260710","title":"Planos de arquitectura de la sala de bombas contra incendios","date":"2026-07-10","sheet":"Arquitectura A103 / p. 5; Estructura A201 / p. 4"} | ["Envolvente exterior controlada por la planta de arquitectura; no se han modelado individualmente todas las capas de acabado.","Registro de líneas del PDF general con envolvente de 10,2 × 8,2 m. Estimación de trabajo de implantación de ±0,15 m, pendiente de CAD nativo; no constituye una precisión topográfica garantizada."] | {"horizontalStatus":"derivado","verticalStatus":"derivado","baseElevationM":286.25,"note":"Registro de líneas del PDF general con envolvente de 10,2 × 8,2 m. Estimación de trabajo de implantación de ±0,15 m, pendiente de CAD nativo; no constituye una precisión topográfica garantizada."} | {"Pset_WallCommon":{"IsExternal":{"value":true,"source":"ARQ-SB-20260710 · A101, A103 y alzados; elemento de la envolvente exterior identificada en planta","status":"known"}}} | {"boundingBoxM":{"min":[15.050857,25.676976,1.25],"max":[16.266915,26.038557,2.45]},"extentsM":[1.216058,0.361581,1.2],"meshSurfaceM2":3.840002,"meshVolumeM3":0.288001,"closedSolid":true,"basis":"Geometría triangulada releída del IFC; envolventes y magnitudes no contractuales."} | {"material":true,"document":true,"quantities":true,"containerGuid":"0Wh59pm9LO_einrwiq6Es1","containerName":"Planta baja"} | {"id":"architecture","name":"Arquitectura"} | {"profileId":"concrete_precast","name":"Hormigón prefabricado","materialName":"Hormigón prefabricado macizo","physicalMaterialStatus":"known","physicalMaterialSource":"ARQ-SB-20260710 · Arquitectura A103 / p. 5; Estructura A201 / p. 4","appearanceStatus":"criterio_visual","appearanceBasis":"Interpretación visual del material documental; el acabado, tono y parámetros PBR no son una especificación contractual.","note":"La apariencia gráfica no modifica ni confirma la especificación física del material."} | {"elementId":"pump_house_0005","ifcGuid":"34oyj_Bu9OkQwRjklDWEvS","ifcClass":"IfcWall","buildingId":"pump_house","buildingName":"Sala de bombas contra incendios","sourceDocumentId":"ARQ-SB-20260710","sourceRepresentationKind":"documentary_mesh"} | {"layerId":"architecture","layerName":"Arquitectura","role":"Muro","basis":"Clasificación por función del elemento; no modifica las especificaciones documentales."} | architecture | {"profileId":"concrete_precast","name":"Hormigón prefabricado","status":"criterio_visual","basis":"Interpretación visual del material documental; el acabado, tono y parámetros PBR no son una especificación contractual.","physicalMaterialUnchanged":true} | ARQ-SB-20260710 · Arquitectura A103 / p. 5; Estructura A201 / p. 4 | Dimensiones contrastadas con los planos; reconstrucción geométrica a partir de documentación de diseño. | 0.2 | Muros segmentados con huecos reales para puertas y ventanas. | Envolvente exterior controlada por la planta de arquitectura; no se han modelado individualmente todas las capas de acabado. | Registro de líneas del PDF general con envolvente de 10,2 × 8,2 m. Estimación de trabajo de implantación de ±0,15 m, pendiente de CAD nativo; no constituye una precisión topográfica garantizada. | Arquitectura | ARQ-SB-20260710 · Arquitectura A103 / p. 5; Estructura A201 / p. 4 | 286.25 | Arquitectura | Hormigón prefabricado | concrete_precast | [0.756863,0.752941,0.717647] | 0.86 | 0 | Interpretación visual del material documental; el acabado, tono y parámetros PBR no son una especificación contractual. | Arquitectura; BIM · Arquitectura
Sala de bombas contra incendios · Zócalo de hormigón · eje A · tramo 05 | Planos de arquitectura de la sala de bombas contra incendios; Planos de arquitectura de la sala de bombas contra incendios | Hormigón prefabricado macizo | 2 × 0.2 × 1.2 | 286.25 | 287.45 | 0.48 | pump_house_0006 | yes | 2.0086 | 0.470544 | 1.2 | 6.08 | 0.480001 | pump_house | Sala de bombas contra incendios | {"name":"Hormigón prefabricado macizo","source":"ARQ-SB-20260710 · Arquitectura A103 / p. 5; Estructura A201 / p. 4","status":"known"} | {"documented":[{"label":"Espesor del muro","value":0.2,"unit":"m","source":"ARQ-SB-20260710 · Arquitectura A103 / p. 5; Estructura A201 / p. 4","status":"documentado"}],"geometry":[{"label":"Dimensiones de la caja local del elemento (X, Y, Z)","value":"2 × 0.2 × 1.2","unit":"m","source":"Malla triangulada del elemento en ejes locales del edificio","status":"derivado"},{"label":"Cota mínima absoluta de la malla","value":286.25,"unit":"m","source":"Malla de proyecto y origen altimétrico 285 m","status":"derivado"},{"label":"Cota máxima absoluta de la malla","value":287.45,"unit":"m","source":"Malla de proyecto y origen altimétrico 285 m","status":"derivado"},{"label":"Volumen geométrico bruto","value":0.48,"unit":"m³","source":"Malla cerrada del elemento","status":"derivado"}],"notes":["Las dimensiones documentadas proceden de anotaciones o cuadros; la caja y el volumen se calculan a partir de la malla.","El volumen es exclusivamente geométrico y bruto; no representa una medición neta de material ni una cantidad de compra."]} | {"documentId":"ARQ-SB-20260710","title":"Planos de arquitectura de la sala de bombas contra incendios","date":"2026-07-10","sheet":"Arquitectura A103 / p. 5; Estructura A201 / p. 4"} | ["Envolvente exterior controlada por la planta de arquitectura; no se han modelado individualmente todas las capas de acabado.","Registro de líneas del PDF general con envolvente de 10,2 × 8,2 m. Estimación de trabajo de implantación de ±0,15 m, pendiente de CAD nativo; no constituye una precisión topográfica garantizada."] | {"horizontalStatus":"derivado","verticalStatus":"derivado","baseElevationM":286.25,"note":"Registro de líneas del PDF general con envolvente de 10,2 × 8,2 m. Estimación de trabajo de implantación de ±0,15 m, pendiente de CAD nativo; no constituye una precisión topográfica garantizada."} | {"Pset_WallCommon":{"IsExternal":{"value":true,"source":"ARQ-SB-20260710 · A101, A103 y alzados; elemento de la envolvente exterior identificada en planta","status":"known"}}} | {"boundingBoxM":{"min":[16.239674,25.404569,1.25],"max":[18.248277,25.875113,2.45]},"extentsM":[2.008603,0.470544,1.2],"meshSurfaceM2":6.080003,"meshVolumeM3":0.480001,"closedSolid":true,"basis":"Geometría triangulada releída del IFC; envolventes y magnitudes no contractuales."} | {"material":true,"document":true,"quantities":true,"containerGuid":"0Wh59pm9LO_einrwiq6Es1","containerName":"Planta baja"} | {"id":"architecture","name":"Arquitectura"} | {"profileId":"concrete_precast","name":"Hormigón prefabricado","materialName":"Hormigón prefabricado macizo","physicalMaterialStatus":"known","physicalMaterialSource":"ARQ-SB-20260710 · Arquitectura A103 / p. 5; Estructura A201 / p. 4","appearanceStatus":"criterio_visual","appearanceBasis":"Interpretación visual del material documental; el acabado, tono y parámetros PBR no son una especificación contractual.","note":"La apariencia gráfica no modifica ni confirma la especificación física del material."} | {"elementId":"pump_house_0006","ifcGuid":"17L9O3aLTNfwmfgt66OfTL","ifcClass":"IfcWall","buildingId":"pump_house","buildingName":"Sala de bombas contra incendios","sourceDocumentId":"ARQ-SB-20260710","sourceRepresentationKind":"documentary_mesh"} | {"layerId":"architecture","layerName":"Arquitectura","role":"Muro","basis":"Clasificación por función del elemento; no modifica las especificaciones documentales."} | architecture | {"profileId":"concrete_precast","name":"Hormigón prefabricado","status":"criterio_visual","basis":"Interpretación visual del material documental; el acabado, tono y parámetros PBR no son una especificación contractual.","physicalMaterialUnchanged":true} | ARQ-SB-20260710 · Arquitectura A103 / p. 5; Estructura A201 / p. 4 | Dimensiones contrastadas con los planos; reconstrucción geométrica a partir de documentación de diseño. | 0.2 | Muros segmentados con huecos reales para puertas y ventanas. | Envolvente exterior controlada por la planta de arquitectura; no se han modelado individualmente todas las capas de acabado. | Registro de líneas del PDF general con envolvente de 10,2 × 8,2 m. Estimación de trabajo de implantación de ±0,15 m, pendiente de CAD nativo; no constituye una precisión topográfica garantizada. | Arquitectura | ARQ-SB-20260710 · Arquitectura A103 / p. 5; Estructura A201 / p. 4 | 286.25 | Arquitectura | Hormigón prefabricado | concrete_precast | [0.756863,0.752941,0.717647] | 0.86 | 0 | Interpretación visual del material documental; el acabado, tono y parámetros PBR no son una especificación contractual. | Arquitectura; BIM · Arquitectura
Sala de bombas contra incendios · Panel sándwich de fachada con núcleo de lana de roca · eje A · tramo 01 | Planos de arquitectura de la sala de bombas contra incendios; Planos de arquitectura de la sala de bombas contra incendios | Panel sándwich de acero con núcleo de lana de roca | 2 × 0.1 × 0.3 | 287.45 | 287.75 | 0.06 | pump_house_0007 | yes | 1.99498 | 0.371476 | 0.3 | 1.66 | 0.06 | pump_house | Sala de bombas contra incendios | {"name":"Panel sándwich de acero con núcleo de lana de roca","source":"ARQ-SB-20260710 · Arquitectura A103 / p. 5; A301Cuadro de materiales ; ARQ-OF-20260710 · A301 / p. 16, bloque correspondiente a la sala de bombas","status":"known"} | {"documented":[{"label":"Espesor del muro","value":0.1,"unit":"m","source":"ARQ-SB-20260710 · Arquitectura A103 / p. 5; A301Cuadro de materiales ","status":"documentado"}],"geometry":[{"label":"Dimensiones de la caja local del elemento (X, Y, Z)","value":"2 × 0.1 × 0.3","unit":"m","source":"Malla triangulada del elemento en ejes locales del edificio","status":"derivado"},{"label":"Cota mínima absoluta de la malla","value":287.45,"unit":"m","source":"Malla de proyecto y origen altimétrico 285 m","status":"derivado"},{"label":"Cota máxima absoluta de la malla","value":287.75,"unit":"m","source":"Malla de proyecto y origen altimétrico 285 m","status":"derivado"},{"label":"Volumen geométrico bruto","value":0.06,"unit":"m³","source":"Malla cerrada del elemento","status":"derivado"}],"notes":["Las dimensiones documentadas proceden de anotaciones o cuadros; la caja y el volumen se calculan a partir de la malla.","El volumen es exclusivamente geométrico y bruto; no representa una medición neta de material ni una cantidad de compra."]} | {"documentId":"ARQ-SB-20260710","title":"Planos de arquitectura de la sala de bombas contra incendios","date":"2026-07-10","sheet":"Arquitectura A103 / p. 5; A301Cuadro de materiales "} | ["Envolvente exterior controlada por la planta de arquitectura; no se han modelado individualmente todas las capas de acabado.","Registro de líneas del PDF general con envolvente de 10,2 × 8,2 m. Estimación de trabajo de implantación de ±0,15 m, pendiente de CAD nativo; no constituye una precisión topográfica garantizada."] | {"horizontalStatus":"derivado","verticalStatus":"derivado","baseElevationM":286.25,"note":"Registro de líneas del PDF general con envolvente de 10,2 × 8,2 m. Estimación de trabajo de implantación de ±0,15 m, pendiente de CAD nativo; no constituye una precisión topográfica garantizada."} | {"Pset_WallCommon":{"IsExternal":{"value":true,"source":"ARQ-SB-20260710 · A101, A103 y alzados; elemento de la envolvente exterior identificada en planta","status":"known"}}} | {"boundingBoxM":{"min":[8.116092,26.521441,2.45],"max":[10.111074,26.892917,2.75]},"extentsM":[1.994982,0.371476,0.3],"meshSurfaceM2":1.66,"meshVolumeM3":0.06,"closedSolid":true,"basis":"Geometría triangulada releída del IFC; envolventes y magnitudes no contractuales."} | {"material":true,"document":true,"quantities":true,"containerGuid":"0Wh59pm9LO_einrwiq6Es1","containerName":"Planta baja"} | {"id":"architecture","name":"Arquitectura"} | {"profileId":"sandwich_panel","name":"Panel sándwich · chapa gris clara","materialName":"Panel sándwich de acero con núcleo de lana de roca","physicalMaterialStatus":"known","physicalMaterialSource":"ARQ-SB-20260710 · Arquitectura A103 / p. 5; A301Cuadro de materiales ; ARQ-OF-20260710 · A301 / p. 16, bloque correspondiente a la sala de bombas","appearanceStatus":"criterio_visual","appearanceBasis":"Interpretación visual del material documental; el acabado, tono y parámetros PBR no son una especificación contractual.","note":"La apariencia gráfica no modifica ni confirma la especificación física del material."} | {"elementId":"pump_house_0007","ifcGuid":"0HUTVNUaHPPeMbzLH0cDUD","ifcClass":"IfcWall","buildingId":"pump_house","buildingName":"Sala de bombas contra incendios","sourceDocumentId":"ARQ-SB-20260710","sourceRepresentationKind":"documentary_mesh"} | {"layerId":"architecture","layerName":"Arquitectura","role":"Muro","basis":"Clasificación por función del elemento; no modifica las especificaciones documentales."} | architecture | {"profileId":"sandwich_panel","name":"Panel sándwich · chapa gris clara","status":"criterio_visual","basis":"Interpretación visual del material documental; el acabado, tono y parámetros PBR no son una especificación contractual.","physicalMaterialUnchanged":true} | ARQ-SB-20260710 · Arquitectura A103 / p. 5; A301Cuadro de materiales | Dimensiones contrastadas con los planos; reconstrucción geométrica a partir de documentación de diseño. | 0.1 | Muros segmentados con huecos reales para puertas y ventanas. | Envolvente exterior controlada por la planta de arquitectura; no se han modelado individualmente todas las capas de acabado. | Registro de líneas del PDF general con envolvente de 10,2 × 8,2 m. Estimación de trabajo de implantación de ±0,15 m, pendiente de CAD nativo; no constituye una precisión topográfica garantizada. | Arquitectura | ARQ-SB-20260710 · Arquitectura A103 / p. 5; A301Cuadro de materiales ; ARQ-OF-20260710 · A301 / p. 16, bloque correspondiente a la sala de bombas | 286.25 | Arquitectura | Panel sándwich · chapa gris clara | sandwich_panel | [0.85098,0.87451,0.87451] | 0.48 | 0.28 | Interpretación visual del material documental; el acabado, tono y parámetros PBR no son una especificación contractual. | Arquitectura; BIM · Arquitectura
Sala de bombas contra incendios · Panel sándwich de fachada con núcleo de lana de roca · eje A · tramo 02 | Planos de arquitectura de la sala de bombas contra incendios; Planos de arquitectura de la sala de bombas contra incendios | Panel sándwich de acero con núcleo de lana de roca | 2 × 0.1 × 2.6 | 287.75 | 290.35 | 0.52 | pump_house_0008 | yes | 1.99498 | 0.371476 | 2.6 | 11.32 | 0.52 | pump_house | Sala de bombas contra incendios | {"name":"Panel sándwich de acero con núcleo de lana de roca","source":"ARQ-SB-20260710 · Arquitectura A103 / p. 5; A301Cuadro de materiales ; ARQ-OF-20260710 · A301 / p. 16, bloque correspondiente a la sala de bombas","status":"known"} | {"documented":[{"label":"Espesor del muro","value":0.1,"unit":"m","source":"ARQ-SB-20260710 · Arquitectura A103 / p. 5; A301Cuadro de materiales ","status":"documentado"}],"geometry":[{"label":"Dimensiones de la caja local del elemento (X, Y, Z)","value":"2 × 0.1 × 2.6","unit":"m","source":"Malla triangulada del elemento en ejes locales del edificio","status":"derivado"},{"label":"Cota mínima absoluta de la malla","value":287.75,"unit":"m","source":"Malla de proyecto y origen altimétrico 285 m","status":"derivado"},{"label":"Cota máxima absoluta de la malla","value":290.35,"unit":"m","source":"Malla de proyecto y origen altimétrico 285 m","status":"derivado"},{"label":"Volumen geométrico bruto","value":0.52,"unit":"m³","source":"Malla cerrada del elemento","status":"derivado"}],"notes":["Las dimensiones documentadas proceden de anotaciones o cuadros; la caja y el volumen se calculan a partir de la malla.","El volumen es exclusivamente geométrico y bruto; no representa una medición neta de material ni una cantidad de compra."]} | {"documentId":"ARQ-SB-20260710","title":"Planos de arquitectura de la sala de bombas contra incendios","date":"2026-07-10","sheet":"Arquitectura A103 / p. 5; A301Cuadro de materiales "} | ["Envolvente exterior controlada por la planta de arquitectura; no se han modelado individualmente todas las capas de acabado.","Registro de líneas del PDF general con envolvente de 10,2 × 8,2 m. Estimación de trabajo de implantación de ±0,15 m, pendiente de CAD nativo; no constituye una precisión topográfica garantizada."] | {"horizontalStatus":"derivado","verticalStatus":"derivado","baseElevationM":286.25,"note":"Registro de líneas del PDF general con envolvente de 10,2 × 8,2 m. Estimación de trabajo de implantación de ±0,15 m, pendiente de CAD nativo; no constituye una precisión topográfica garantizada."} | {"Pset_WallCommon":{"IsExternal":{"value":true,"source":"ARQ-SB-20260710 · A101, A103 y alzados; elemento de la envolvente exterior identificada en planta","status":"known"}}} | {"boundingBoxM":{"min":[8.116092,26.521441,2.75],"max":[10.111074,26.892917,5.35]},"extentsM":[1.994982,0.371476,2.6],"meshSurfaceM2":11.319999,"meshVolumeM3":0.52,"closedSolid":true,"basis":"Geometría triangulada releída del IFC; envolventes y magnitudes no contractuales."} | {"material":true,"document":true,"quantities":true,"containerGuid":"0Wh59pm9LO_einrwiq6Es1","containerName":"Planta baja"} | {"id":"architecture","name":"Arquitectura"} | {"profileId":"sandwich_panel","name":"Panel sándwich · chapa gris clara","materialName":"Panel sándwich de acero con núcleo de lana de roca","physicalMaterialStatus":"known","physicalMaterialSource":"ARQ-SB-20260710 · Arquitectura A103 / p. 5; A301Cuadro de materiales ; ARQ-OF-20260710 · A301 / p. 16, bloque correspondiente a la sala de bombas","appearanceStatus":"criterio_visual","appearanceBasis":"Interpretación visual del material documental; el acabado, tono y parámetros PBR no son una especificación contractual.","note":"La apariencia gráfica no modifica ni confirma la especificación física del material."} | {"elementId":"pump_house_0008","ifcGuid":"2lT6LV1jjKqOM0VOndUc4r","ifcClass":"IfcWall","buildingId":"pump_house","buildingName":"Sala de bombas contra incendios","sourceDocumentId":"ARQ-SB-20260710","sourceRepresentationKind":"documentary_mesh"} | {"layerId":"architecture","layerName":"Arquitectura","role":"Muro","basis":"Clasificación por función del elemento; no modifica las especificaciones documentales."} | architecture | {"profileId":"sandwich_panel","name":"Panel sándwich · chapa gris clara","status":"criterio_visual","basis":"Interpretación visual del material documental; el acabado, tono y parámetros PBR no son una especificación contractual.","physicalMaterialUnchanged":true} | ARQ-SB-20260710 · Arquitectura A103 / p. 5; A301Cuadro de materiales | Dimensiones contrastadas con los planos; reconstrucción geométrica a partir de documentación de diseño. | 0.1 | Muros segmentados con huecos reales para puertas y ventanas. | Envolvente exterior controlada por la planta de arquitectura; no se han modelado individualmente todas las capas de acabado. | Registro de líneas del PDF general con envolvente de 10,2 × 8,2 m. Estimación de trabajo de implantación de ±0,15 m, pendiente de CAD nativo; no constituye una precisión topográfica garantizada. | Arquitectura | ARQ-SB-20260710 · Arquitectura A103 / p. 5; A301Cuadro de materiales ; ARQ-OF-20260710 · A301 / p. 16, bloque correspondiente a la sala de bombas | 286.25 | Arquitectura | Panel sándwich · chapa gris clara | sandwich_panel | [0.85098,0.87451,0.87451] | 0.48 | 0.28 | Interpretación visual del material documental; el acabado, tono y parámetros PBR no son una especificación contractual. | Arquitectura; BIM · Arquitectura
Sala de bombas contra incendios · Panel sándwich de fachada con núcleo de lana de roca · eje A · tramo 03 | Planos de arquitectura de la sala de bombas contra incendios; Planos de arquitectura de la sala de bombas contra incendios | Panel sándwich de acero con núcleo de lana de roca | 2 × 0.1 × 1.5 | 290.35 | 291.85 | 0.3 | pump_house_0009 | yes | 1.99498 | 0.371476 | 1.5 | 6.7 | 0.3 | pump_house | Sala de bombas contra incendios | {"name":"Panel sándwich de acero con núcleo de lana de roca","source":"ARQ-SB-20260710 · Arquitectura A103 / p. 5; A301Cuadro de materiales ; ARQ-OF-20260710 · A301 / p. 16, bloque correspondiente a la sala de bombas","status":"known"} | {"documented":[{"label":"Espesor del muro","value":0.1,"unit":"m","source":"ARQ-SB-20260710 · Arquitectura A103 / p. 5; A301Cuadro de materiales ","status":"documentado"}],"geometry":[{"label":"Dimensiones de la caja local del elemento (X, Y, Z)","value":"2 × 0.1 × 1.5","unit":"m","source":"Malla triangulada del elemento en ejes locales del edificio","status":"derivado"},{"label":"Cota mínima absoluta de la malla","value":290.35,"unit":"m","source":"Malla de proyecto y origen altimétrico 285 m","status":"derivado"},{"label":"Cota máxima absoluta de la malla","value":291.85,"unit":"m","source":"Malla de proyecto y origen altimétrico 285 m","status":"derivado"},{"label":"Volumen geométrico bruto","value":0.3,"unit":"m³","source":"Malla cerrada del elemento","status":"derivado"}],"notes":["Las dimensiones documentadas proceden de anotaciones o cuadros; la caja y el volumen se calculan a partir de la malla.","El volumen es exclusivamente geométrico y bruto; no representa una medición neta de material ni una cantidad de compra."]} | {"documentId":"ARQ-SB-20260710","title":"Planos de arquitectura de la sala de bombas contra incendios","date":"2026-07-10","sheet":"Arquitectura A103 / p. 5; A301Cuadro de materiales "} | ["Envolvente exterior controlada por la planta de arquitectura; no se han modelado individualmente todas las capas de acabado.","Registro de líneas del PDF general con envolvente de 10,2 × 8,2 m. Estimación de trabajo de implantación de ±0,15 m, pendiente de CAD nativo; no constituye una precisión topográfica garantizada."] | {"horizontalStatus":"derivado","verticalStatus":"derivado","baseElevationM":286.25,"note":"Registro de líneas del PDF general con envolvente de 10,2 × 8,2 m. Estimación de trabajo de implantación de ±0,15 m, pendiente de CAD nativo; no constituye una precisión topográfica garantizada."} | {"Pset_WallCommon":{"IsExternal":{"value":true,"source":"ARQ-SB-20260710 · A101, A103 y alzados; elemento de la envolvente exterior identificada en planta","status":"known"}}} | {"boundingBoxM":{"min":[8.116092,26.521441,5.35],"max":[10.111074,26.892917,6.85]},"extentsM":[1.994982,0.371476,1.5],"meshSurfaceM2":6.699999,"meshVolumeM3":0.3,"closedSolid":true,"basis":"Geometría triangulada releída del IFC; envolventes y magnitudes no contractuales."} | {"material":true,"document":true,"quantities":true,"containerGuid":"0Wh59pm9LO_einrwiq6Es1","containerName":"Planta baja"} | {"id":"architecture","name":"Arquitectura"} | {"profileId":"sandwich_panel","name":"Panel sándwich · chapa gris clara","materialName":"Panel sándwich de acero con núcleo de lana de roca","physicalMaterialStatus":"known","physicalMaterialSource":"ARQ-SB-20260710 · Arquitectura A103 / p. 5; A301Cuadro de materiales ; ARQ-OF-20260710 · A301 / p. 16, bloque correspondiente a la sala de bombas","appearanceStatus":"criterio_visual","appearanceBasis":"Interpretación visual del material documental; el acabado, tono y parámetros PBR no son una especificación contractual.","note":"La apariencia gráfica no modifica ni confirma la especificación física del material."} | {"elementId":"pump_house_0009","ifcGuid":"1EZ$RDr_TNu9d$Ur0ngkqa","ifcClass":"IfcWall","buildingId":"pump_house","buildingName":"Sala de bombas contra incendios","sourceDocumentId":"ARQ-SB-20260710","sourceRepresentationKind":"documentary_mesh"} | {"layerId":"architecture","layerName":"Arquitectura","role":"Muro","basis":"Clasificación por función del elemento; no modifica las especificaciones documentales."} | architecture | {"profileId":"sandwich_panel","name":"Panel sándwich · chapa gris clara","status":"criterio_visual","basis":"Interpretación visual del material documental; el acabado, tono y parámetros PBR no son una especificación contractual.","physicalMaterialUnchanged":true} | ARQ-SB-20260710 · Arquitectura A103 / p. 5; A301Cuadro de materiales | Dimensiones contrastadas con los planos; reconstrucción geométrica a partir de documentación de diseño. | 0.1 | Muros segmentados con huecos reales para puertas y ventanas. | Envolvente exterior controlada por la planta de arquitectura; no se han modelado individualmente todas las capas de acabado. | Registro de líneas del PDF general con envolvente de 10,2 × 8,2 m. Estimación de trabajo de implantación de ±0,15 m, pendiente de CAD nativo; no constituye una precisión topográfica garantizada. | Arquitectura | ARQ-SB-20260710 · Arquitectura A103 / p. 5; A301Cuadro de materiales ; ARQ-OF-20260710 · A301 / p. 16, bloque correspondiente a la sala de bombas | 286.25 | Arquitectura | Panel sándwich · chapa gris clara | sandwich_panel | [0.85098,0.87451,0.87451] | 0.48 | 0.28 | Interpretación visual del material documental; el acabado, tono y parámetros PBR no son una especificación contractual. | Arquitectura; BIM · Arquitectura
Sala de bombas contra incendios · Panel sándwich de fachada con núcleo de lana de roca · eje A · tramo 04 | Planos de arquitectura de la sala de bombas contra incendios; Planos de arquitectura de la sala de bombas contra incendios | Panel sándwich de acero con núcleo de lana de roca | 1.2 × 0.1 × 0.3 | 287.45 | 287.75 | 0.036 | pump_house_0010 | yes | 1.20244 | 0.262513 | 0.3 | 1.02 | 0.036 | pump_house | Sala de bombas contra incendios | {"name":"Panel sándwich de acero con núcleo de lana de roca","source":"ARQ-SB-20260710 · Arquitectura A103 / p. 5; A301Cuadro de materiales ; ARQ-OF-20260710 · A301 / p. 16, bloque correspondiente a la sala de bombas","status":"known"} | {"documented":[{"label":"Espesor del muro","value":0.1,"unit":"m","source":"ARQ-SB-20260710 · Arquitectura A103 / p. 5; A301Cuadro de materiales ","status":"documentado"}],"geometry":[{"label":"Dimensiones de la caja local del elemento (X, Y, Z)","value":"1.2 × 0.1 × 0.3","unit":"m","source":"Malla triangulada del elemento en ejes locales del edificio","status":"derivado"},{"label":"Cota mínima absoluta de la malla","value":287.45,"unit":"m","source":"Malla de proyecto y origen altimétrico 285 m","status":"derivado"},{"label":"Cota máxima absoluta de la malla","value":287.75,"unit":"m","source":"Malla de proyecto y origen altimétrico 285 m","status":"derivado"},{"label":"Volumen geométrico bruto","value":0.036,"unit":"m³","source":"Malla cerrada del elemento","status":"derivado"}],"notes":["Las dimensiones documentadas proceden de anotaciones o cuadros; la caja y el volumen se calculan a partir de la malla.","El volumen es exclusivamente geométrico y bruto; no representa una medición neta de material ni una cantidad de compra."]} | {"documentId":"ARQ-SB-20260710","title":"Planos de arquitectura de la sala de bombas contra incendios","date":"2026-07-10","sheet":"Arquitectura A103 / p. 5; A301Cuadro de materiales "} | ["Envolvente exterior controlada por la planta de arquitectura; no se han modelado individualmente todas las capas de acabado.","Registro de líneas del PDF general con envolvente de 10,2 × 8,2 m. Estimación de trabajo de implantación de ±0,15 m, pendiente de CAD nativo; no constituye una precisión topográfica garantizada."] | {"horizontalStatus":"derivado","verticalStatus":"derivado","baseElevationM":286.25,"note":"Registro de líneas del PDF general con envolvente de 10,2 × 8,2 m. Estimación de trabajo de implantación de ±0,15 m, pendiente de CAD nativo; no constituye una precisión topográfica garantizada."} | {"Pset_WallCommon":{"IsExternal":{"value":true,"source":"ARQ-SB-20260710 · A101, A103 y alzados; elemento de la envolvente exterior identificada en planta","status":"known"}}} | {"boundingBoxM":{"min":[10.097453,26.357996,2.45],"max":[11.299891,26.620509,2.75]},"extentsM":[1.202438,0.262513,0.3],"meshSurfaceM2":1.02,"meshVolumeM3":0.036,"closedSolid":true,"basis":"Geometría triangulada releída del IFC; envolventes y magnitudes no contractuales."} | {"material":true,"document":true,"quantities":true,"containerGuid":"0Wh59pm9LO_einrwiq6Es1","containerName":"Planta baja"} | {"id":"architecture","name":"Arquitectura"} | {"profileId":"sandwich_panel","name":"Panel sándwich · chapa gris clara","materialName":"Panel sándwich de acero con núcleo de lana de roca","physicalMaterialStatus":"known","physicalMaterialSource":"ARQ-SB-20260710 · Arquitectura A103 / p. 5; A301Cuadro de materiales ; ARQ-OF-20260710 · A301 / p. 16, bloque correspondiente a la sala de bombas","appearanceStatus":"criterio_visual","appearanceBasis":"Interpretación visual del material documental; el acabado, tono y parámetros PBR no son una especificación contractual.","note":"La apariencia gráfica no modifica ni confirma la especificación física del material."} | {"elementId":"pump_house_0010","ifcGuid":"1eOymtbG1GmQuF6a7ImaUT","ifcClass":"IfcWall","buildingId":"pump_house","buildingName":"Sala de bombas contra incendios","sourceDocumentId":"ARQ-SB-20260710","sourceRepresentationKind":"documentary_mesh"} | {"layerId":"architecture","layerName":"Arquitectura","role":"Muro","basis":"Clasificación por función del elemento; no modifica las especificaciones documentales."} | architecture | {"profileId":"sandwich_panel","name":"Panel sándwich · chapa gris clara","status":"criterio_visual","basis":"Interpretación visual del material documental; el acabado, tono y parámetros PBR no son una especificación contractual.","physicalMaterialUnchanged":true} | ARQ-SB-20260710 · Arquitectura A103 / p. 5; A301Cuadro de materiales | Dimensiones contrastadas con los planos; reconstrucción geométrica a partir de documentación de diseño. | 0.1 | Muros segmentados con huecos reales para puertas y ventanas. | Envolvente exterior controlada por la planta de arquitectura; no se han modelado individualmente todas las capas de acabado. | Registro de líneas del PDF general con envolvente de 10,2 × 8,2 m. Estimación de trabajo de implantación de ±0,15 m, pendiente de CAD nativo; no constituye una precisión topográfica garantizada. | Arquitectura | ARQ-SB-20260710 · Arquitectura A103 / p. 5; A301Cuadro de materiales ; ARQ-OF-20260710 · A301 / p. 16, bloque correspondiente a la sala de bombas | 286.25 | Arquitectura | Panel sándwich · chapa gris clara | sandwich_panel | [0.85098,0.87451,0.87451] | 0.48 | 0.28 | Interpretación visual del material documental; el acabado, tono y parámetros PBR no son una especificación contractual. | Arquitectura; BIM · Arquitectura
Sala de bombas contra incendios · Panel sándwich de fachada con núcleo de lana de roca · eje A · tramo 05 | Planos de arquitectura de la sala de bombas contra incendios; Planos de arquitectura de la sala de bombas contra incendios | Panel sándwich de acero con núcleo de lana de roca | 1.2 × 0.1 × 1.5 | 290.35 | 291.85 | 0.18 | pump_house_0011 | yes | 1.20244 | 0.262513 | 1.5 | 4.14 | 0.18 | pump_house | Sala de bombas contra incendios | {"name":"Panel sándwich de acero con núcleo de lana de roca","source":"ARQ-SB-20260710 · Arquitectura A103 / p. 5; A301Cuadro de materiales ; ARQ-OF-20260710 · A301 / p. 16, bloque correspondiente a la sala de bombas","status":"known"} | {"documented":[{"label":"Espesor del muro","value":0.1,"unit":"m","source":"ARQ-SB-20260710 · Arquitectura A103 / p. 5; A301Cuadro de materiales ","status":"documentado"}],"geometry":[{"label":"Dimensiones de la caja local del elemento (X, Y, Z)","value":"1.2 × 0.1 × 1.5","unit":"m","source":"Malla triangulada del elemento en ejes locales del edificio","status":"derivado"},{"label":"Cota mínima absoluta de la malla","value":290.35,"unit":"m","source":"Malla de proyecto y origen altimétrico 285 m","status":"derivado"},{"label":"Cota máxima absoluta de la malla","value":291.85,"unit":"m","source":"Malla de proyecto y origen altimétrico 285 m","status":"derivado"},{"label":"Volumen geométrico bruto","value":0.18,"unit":"m³","source":"Malla cerrada del elemento","status":"derivado"}],"notes":["Las dimensiones documentadas proceden de anotaciones o cuadros; la caja y el volumen se calculan a partir de la malla.","El volumen es exclusivamente geométrico y bruto; no representa una medición neta de material ni una cantidad de compra."]} | {"documentId":"ARQ-SB-20260710","title":"Planos de arquitectura de la sala de bombas contra incendios","date":"2026-07-10","sheet":"Arquitectura A103 / p. 5; A301Cuadro de materiales "} | ["Envolvente exterior controlada por la planta de arquitectura; no se han modelado individualmente todas las capas de acabado.","Registro de líneas del PDF general con envolvente de 10,2 × 8,2 m. Estimación de trabajo de implantación de ±0,15 m, pendiente de CAD nativo; no constituye una precisión topográfica garantizada."] | {"horizontalStatus":"derivado","verticalStatus":"derivado","baseElevationM":286.25,"note":"Registro de líneas del PDF general con envolvente de 10,2 × 8,2 m. Estimación de trabajo de implantación de ±0,15 m, pendiente de CAD nativo; no constituye una precisión topográfica garantizada."} | {"Pset_WallCommon":{"IsExternal":{"value":true,"source":"ARQ-SB-20260710 · A101, A103 y alzados; elemento de la envolvente exterior identificada en planta","status":"known"}}} | {"boundingBoxM":{"min":[10.097453,26.357996,5.35],"max":[11.299891,26.620509,6.85]},"extentsM":[1.202438,0.262513,1.5],"meshSurfaceM2":4.14,"meshVolumeM3":0.18,"closedSolid":true,"basis":"Geometría triangulada releída del IFC; envolventes y magnitudes no contractuales."} | {"material":true,"document":true,"quantities":true,"containerGuid":"0Wh59pm9LO_einrwiq6Es1","containerName":"Planta baja"} | {"id":"architecture","name":"Arquitectura"} | {"profileId":"sandwich_panel","name":"Panel sándwich · chapa gris clara","materialName":"Panel sándwich de acero con núcleo de lana de roca","physicalMaterialStatus":"known","physicalMaterialSource":"ARQ-SB-20260710 · Arquitectura A103 / p. 5; A301Cuadro de materiales ; ARQ-OF-20260710 · A301 / p. 16, bloque correspondiente a la sala de bombas","appearanceStatus":"criterio_visual","appearanceBasis":"Interpretación visual del material documental; el acabado, tono y parámetros PBR no son una especificación contractual.","note":"La apariencia gráfica no modifica ni confirma la especificación física del material."} | {"elementId":"pump_house_0011","ifcGuid":"3udtMCg55TLxaYPXp1lwnd","ifcClass":"IfcWall","buildingId":"pump_house","buildingName":"Sala de bombas contra incendios","sourceDocumentId":"ARQ-SB-20260710","sourceRepresentationKind":"documentary_mesh"} | {"layerId":"architecture","layerName":"Arquitectura","role":"Muro","basis":"Clasificación por función del elemento; no modifica las especificaciones documentales."} | architecture | {"profileId":"sandwich_panel","name":"Panel sándwich · chapa gris clara","status":"criterio_visual","basis":"Interpretación visual del material documental; el acabado, tono y parámetros PBR no son una especificación contractual.","physicalMaterialUnchanged":true} | ARQ-SB-20260710 · Arquitectura A103 / p. 5; A301Cuadro de materiales | Dimensiones contrastadas con los planos; reconstrucción geométrica a partir de documentación de diseño. | 0.1 | Muros segmentados con huecos reales para puertas y ventanas. | Envolvente exterior controlada por la planta de arquitectura; no se han modelado individualmente todas las capas de acabado. | Registro de líneas del PDF general con envolvente de 10,2 × 8,2 m. Estimación de trabajo de implantación de ±0,15 m, pendiente de CAD nativo; no constituye una precisión topográfica garantizada. | Arquitectura | ARQ-SB-20260710 · Arquitectura A103 / p. 5; A301Cuadro de materiales ; ARQ-OF-20260710 · A301 / p. 16, bloque correspondiente a la sala de bombas | 286.25 | Arquitectura | Panel sándwich · chapa gris clara | sandwich_panel | [0.85098,0.87451,0.87451] | 0.48 | 0.28 | Interpretación visual del material documental; el acabado, tono y parámetros PBR no son una especificación contractual. | Arquitectura; BIM · Arquitectura
Sala de bombas contra incendios · Panel sándwich de fachada con núcleo de lana de roca · eje A · tramo 06 | Planos de arquitectura de la sala de bombas contra incendios; Planos de arquitectura de la sala de bombas contra incendios | Panel sándwich de acero con núcleo de lana de roca | 3.8 × 0.1 × 0.3 | 287.45 | 287.75 | 0.114 | pump_house_0012 | yes | 3.77821 | 0.616643 | 0.3 | 3.1 | 0.114 | pump_house | Sala de bombas contra incendios | {"name":"Panel sándwich de acero con núcleo de lana de roca","source":"ARQ-SB-20260710 · Arquitectura A103 / p. 5; A301Cuadro de materiales ; ARQ-OF-20260710 · A301 / p. 16, bloque correspondiente a la sala de bombas","status":"known"} | {"documented":[{"label":"Espesor del muro","value":0.1,"unit":"m","source":"ARQ-SB-20260710 · Arquitectura A103 / p. 5; A301Cuadro de materiales ","status":"documentado"}],"geometry":[{"label":"Dimensiones de la caja local del elemento (X, Y, Z)","value":"3.8 × 0.1 × 0.3","unit":"m","source":"Malla triangulada del elemento en ejes locales del edificio","status":"derivado"},{"label":"Cota mínima absoluta de la malla","value":287.45,"unit":"m","source":"Malla de proyecto y origen altimétrico 285 m","status":"derivado"},{"label":"Cota máxima absoluta de la malla","value":287.75,"unit":"m","source":"Malla de proyecto y origen altimétrico 285 m","status":"derivado"},{"label":"Volumen geométrico bruto","value":0.114,"unit":"m³","source":"Malla cerrada del elemento","status":"derivado"}],"notes":["Las dimensiones documentadas proceden de anotaciones o cuadros; la caja y el volumen se calculan a partir de la malla.","El volumen es exclusivamente geométrico y bruto; no representa una medición neta de material ni una cantidad de compra."]} | {"documentId":"ARQ-SB-20260710","title":"Planos de arquitectura de la sala de bombas contra incendios","date":"2026-07-10","sheet":"Arquitectura A103 / p. 5; A301Cuadro de materiales "} | ["Envolvente exterior controlada por la planta de arquitectura; no se han modelado individualmente todas las capas de acabado.","Registro de líneas del PDF general con envolvente de 10,2 × 8,2 m. Estimación de trabajo de implantación de ±0,15 m, pendiente de CAD nativo; no constituye una precisión topográfica garantizada."] | {"horizontalStatus":"derivado","verticalStatus":"derivado","baseElevationM":286.25,"note":"Registro de líneas del PDF general con envolvente de 10,2 × 8,2 m. Estimación de trabajo de implantación de ±0,15 m, pendiente de CAD nativo; no constituye una precisión topográfica garantizada."} | {"Pset_WallCommon":{"IsExternal":{"value":true,"source":"ARQ-SB-20260710 · A101, A103 y alzados; elemento de la envolvente exterior identificada en planta","status":"known"}}} | {"boundingBoxM":{"min":[11.28627,25.840421,2.45],"max":[15.064478,26.457064,2.75]},"extentsM":[3.778208,0.616643,0.3],"meshSurfaceM2":3.1,"meshVolumeM3":0.114,"closedSolid":true,"basis":"Geometría triangulada releída del IFC; envolventes y magnitudes no contractuales."} | {"material":true,"document":true,"quantities":true,"containerGuid":"0Wh59pm9LO_einrwiq6Es1","containerName":"Planta baja"} | {"id":"architecture","name":"Arquitectura"} | {"profileId":"sandwich_panel","name":"Panel sándwich · chapa gris clara","materialName":"Panel sándwich de acero con núcleo de lana de roca","physicalMaterialStatus":"known","physicalMaterialSource":"ARQ-SB-20260710 · Arquitectura A103 / p. 5; A301Cuadro de materiales ; ARQ-OF-20260710 · A301 / p. 16, bloque correspondiente a la sala de bombas","appearanceStatus":"criterio_visual","appearanceBasis":"Interpretación visual del material documental; el acabado, tono y parámetros PBR no son una especificación contractual.","note":"La apariencia gráfica no modifica ni confirma la especificación física del material."} | {"elementId":"pump_house_0012","ifcGuid":"3TWgXCxNbUn9ODadu50OWb","ifcClass":"IfcWall","buildingId":"pump_house","buildingName":"Sala de bombas contra incendios","sourceDocumentId":"ARQ-SB-20260710","sourceRepresentationKind":"documentary_mesh"} | {"layerId":"architecture","layerName":"Arquitectura","role":"Muro","basis":"Clasificación por función del elemento; no modifica las especificaciones documentales."} | architecture | {"profileId":"sandwich_panel","name":"Panel sándwich · chapa gris clara","status":"criterio_visual","basis":"Interpretación visual del material documental; el acabado, tono y parámetros PBR no son una especificación contractual.","physicalMaterialUnchanged":true} | ARQ-SB-20260710 · Arquitectura A103 / p. 5; A301Cuadro de materiales | Dimensiones contrastadas con los planos; reconstrucción geométrica a partir de documentación de diseño. | 0.1 | Muros segmentados con huecos reales para puertas y ventanas. | Envolvente exterior controlada por la planta de arquitectura; no se han modelado individualmente todas las capas de acabado. | Registro de líneas del PDF general con envolvente de 10,2 × 8,2 m. Estimación de trabajo de implantación de ±0,15 m, pendiente de CAD nativo; no constituye una precisión topográfica garantizada. | Arquitectura | ARQ-SB-20260710 · Arquitectura A103 / p. 5; A301Cuadro de materiales ; ARQ-OF-20260710 · A301 / p. 16, bloque correspondiente a la sala de bombas | 286.25 | Arquitectura | Panel sándwich · chapa gris clara | sandwich_panel | [0.85098,0.87451,0.87451] | 0.48 | 0.28 | Interpretación visual del material documental; el acabado, tono y parámetros PBR no son una especificación contractual. | Arquitectura; BIM · Arquitectura
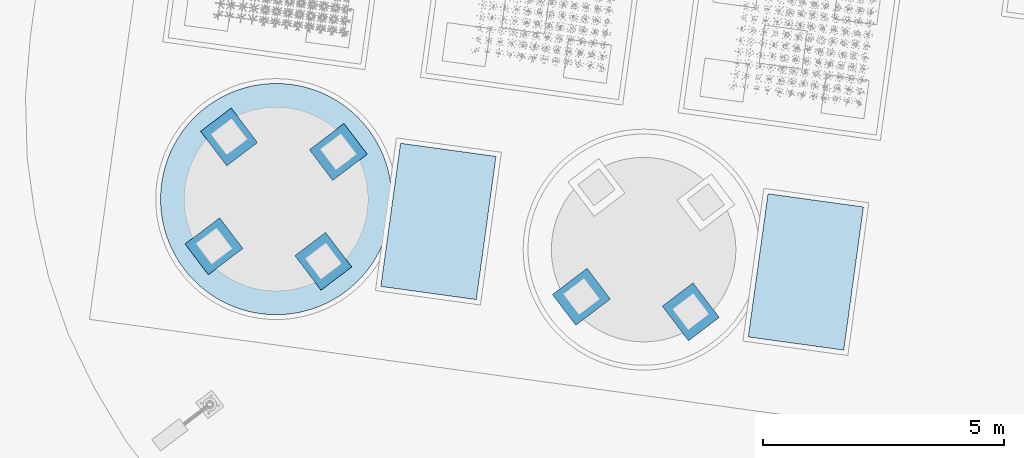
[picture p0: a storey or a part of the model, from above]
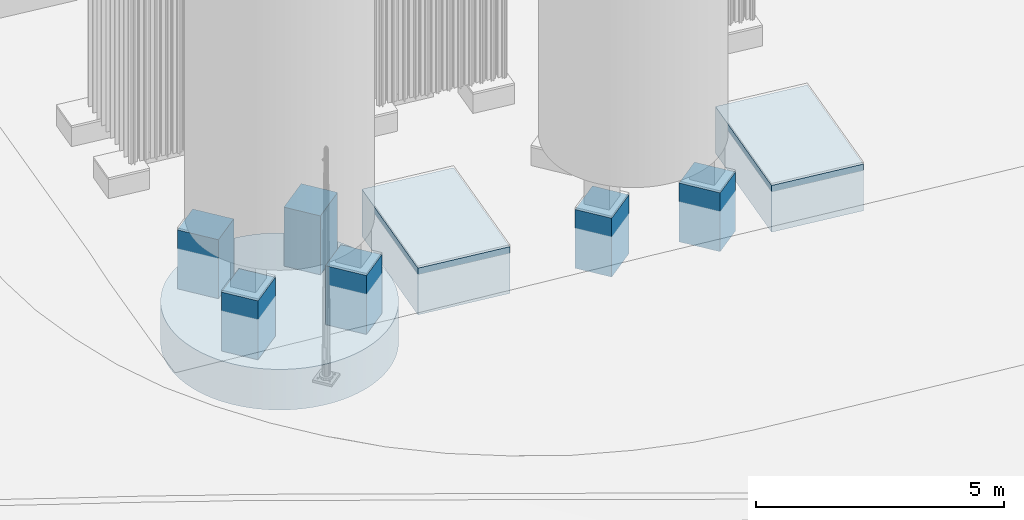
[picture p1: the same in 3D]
Properties of the parts of a building model (IFC4), part 114 of 134

# IfcWall (187)
Name | Document | Material = JH_Trazabilidad, Material = name | Dimensiones de la caja local del elemento (X, Y, Z) | Cota mínima absoluta de la malla (m) | Cota máxima absoluta de la malla (m) | Volumen geométrico bruto (m3) = Volumen geométrico (m³) | Reference = Identificador del elemento = Identificador | IsExternal | ExtensionX (m) | ExtensionY (m) | ExtensionZ (m) | SuperficieDeLaMalla (m2) | VolumenGeometrico (m3) = GrossVolume (m3) | buildingId | buildingName = Edificio | material | dimensions | JH_InformacionBIM, source = DocumentoFuente | issues = IncidenciasPendientes | positioning = PosicionYEstado | commonProperties | geometryMetrics | ifcAssociations | visualLayer | materialAppearance | visualizationIdentity | classification | layerId = IdentificadorCapa | appearance | Planos de referencia | Base geométrica | Espesor del muro (m) = Espesor del muro (m) | Tratamiento de los huecos | Representación de los acabados | Estado de la implantación | Disciplina | Referencia del material = JH_EvidenciaDeMaterial, source | Cota de planta baja terminada (m) | Capa BIM = NombreCapa | Acabado de visualización = Acabado | Perfil | ColorRGB | Rugosidad | Metallicidad | Referencia | Group | Discrepancia entre versiones
Sala de bombas contra incendios · Panel sándwich de fachada con núcleo de lana de roca · eje A · tramo 07 | Planos de arquitectura de la sala de bombas contra incendios; Planos de arquitectura de la sala de bombas contra incendios | Panel sándwich de acero con núcleo de lana de roca | 3.8 × 0.1 × 2.6 | 287.75 | 290.35 | 0.988 | pump_house_0013 | yes | 3.77821 | 0.616643 | 2.6 | 21.04 | 0.988 | pump_house | Sala de bombas contra incendios | {"name":"Panel sándwich de acero con núcleo de lana de roca","source":"ARQ-SB-20260710 · Arquitectura A103 / p. 5; A301Cuadro de materiales ; ARQ-OF-20260710 · A301 / p. 16, bloque correspondiente a la sala de bombas","status":"known"} | {"documented":[{"label":"Espesor del muro","value":0.1,"unit":"m","source":"ARQ-SB-20260710 · Arquitectura A103 / p. 5; A301Cuadro de materiales ","status":"documentado"}],"geometry":[{"label":"Dimensiones de la caja local del elemento (X, Y, Z)","value":"3.8 × 0.1 × 2.6","unit":"m","source":"Malla triangulada del elemento en ejes locales del edificio","status":"derivado"},{"label":"Cota mínima absoluta de la malla","value":287.75,"unit":"m","source":"Malla de proyecto y origen altimétrico 285 m","status":"derivado"},{"label":"Cota máxima absoluta de la malla","value":290.35,"unit":"m","source":"Malla de proyecto y origen altimétrico 285 m","status":"derivado"},{"label":"Volumen geométrico bruto","value":0.988,"unit":"m³","source":"Malla cerrada del elemento","status":"derivado"}],"notes":["Las dimensiones documentadas proceden de anotaciones o cuadros; la caja y el volumen se calculan a partir de la malla.","El volumen es exclusivamente geométrico y bruto; no representa una medición neta de material ni una cantidad de compra."]} | {"documentId":"ARQ-SB-20260710","title":"Planos de arquitectura de la sala de bombas contra incendios","date":"2026-07-10","sheet":"Arquitectura A103 / p. 5; A301Cuadro de materiales "} | ["Envolvente exterior controlada por la planta de arquitectura; no se han modelado individualmente todas las capas de acabado.","Registro de líneas del PDF general con envolvente de 10,2 × 8,2 m. Estimación de trabajo de implantación de ±0,15 m, pendiente de CAD nativo; no constituye una precisión topográfica garantizada."] | {"horizontalStatus":"derivado","verticalStatus":"derivado","baseElevationM":286.25,"note":"Registro de líneas del PDF general con envolvente de 10,2 × 8,2 m. Estimación de trabajo de implantación de ±0,15 m, pendiente de CAD nativo; no constituye una precisión topográfica garantizada."} | {"Pset_WallCommon":{"IsExternal":{"value":true,"source":"ARQ-SB-20260710 · A101, A103 y alzados; elemento de la envolvente exterior identificada en planta","status":"known"}}} | {"boundingBoxM":{"min":[11.28627,25.840421,2.75],"max":[15.064478,26.457064,5.35]},"extentsM":[3.778208,0.616643,2.6],"meshSurfaceM2":21.039999,"meshVolumeM3":0.988,"closedSolid":true,"basis":"Geometría triangulada releída del IFC; envolventes y magnitudes no contractuales."} | {"material":true,"document":true,"quantities":true,"containerGuid":"0Wh59pm9LO_einrwiq6Es1","containerName":"Planta baja"} | {"id":"architecture","name":"Arquitectura"} | {"profileId":"sandwich_panel","name":"Panel sándwich · chapa gris clara","materialName":"Panel sándwich de acero con núcleo de lana de roca","physicalMaterialStatus":"known","physicalMaterialSource":"ARQ-SB-20260710 · Arquitectura A103 / p. 5; A301Cuadro de materiales ; ARQ-OF-20260710 · A301 / p. 16, bloque correspondiente a la sala de bombas","appearanceStatus":"criterio_visual","appearanceBasis":"Interpretación visual del material documental; el acabado, tono y parámetros PBR no son una especificación contractual.","note":"La apariencia gráfica no modifica ni confirma la especificación física del material."} | {"elementId":"pump_house_0013","ifcGuid":"0kNg47lfzHKuhwloFaUUjS","ifcClass":"IfcWall","buildingId":"pump_house","buildingName":"Sala de bombas contra incendios","sourceDocumentId":"ARQ-SB-20260710","sourceRepresentationKind":"documentary_mesh"} | {"layerId":"architecture","layerName":"Arquitectura","role":"Muro","basis":"Clasificación por función del elemento; no modifica las especificaciones documentales."} | architecture | {"profileId":"sandwich_panel","name":"Panel sándwich · chapa gris clara","status":"criterio_visual","basis":"Interpretación visual del material documental; el acabado, tono y parámetros PBR no son una especificación contractual.","physicalMaterialUnchanged":true} | ARQ-SB-20260710 · Arquitectura A103 / p. 5; A301Cuadro de materiales | Dimensiones contrastadas con los planos; reconstrucción geométrica a partir de documentación de diseño. | 0.1 | Muros segmentados con huecos reales para puertas y ventanas. | Envolvente exterior controlada por la planta de arquitectura; no se han modelado individualmente todas las capas de acabado. | Registro de líneas del PDF general con envolvente de 10,2 × 8,2 m. Estimación de trabajo de implantación de ±0,15 m, pendiente de CAD nativo; no constituye una precisión topográfica garantizada. | Arquitectura | ARQ-SB-20260710 · Arquitectura A103 / p. 5; A301Cuadro de materiales ; ARQ-OF-20260710 · A301 / p. 16, bloque correspondiente a la sala de bombas | 286.25 | Arquitectura | Panel sándwich · chapa gris clara | sandwich_panel | [0.85098,0.87451,0.87451] | 0.48 | 0.28 | Interpretación visual del material documental; el acabado, tono y parámetros PBR no son una especificación contractual. | Arquitectura; BIM · Arquitectura
Sala de bombas contra incendios · Panel sándwich de fachada con núcleo de lana de roca · eje A · tramo 08 | Planos de arquitectura de la sala de bombas contra incendios; Planos de arquitectura de la sala de bombas contra incendios | Panel sándwich de acero con núcleo de lana de roca | 3.8 × 0.1 × 1.5 | 290.35 | 291.85 | 0.57 | pump_house_0014 | yes | 3.77821 | 0.616643 | 1.5 | 12.46 | 0.57 | pump_house | Sala de bombas contra incendios | {"name":"Panel sándwich de acero con núcleo de lana de roca","source":"ARQ-SB-20260710 · Arquitectura A103 / p. 5; A301Cuadro de materiales ; ARQ-OF-20260710 · A301 / p. 16, bloque correspondiente a la sala de bombas","status":"known"} | {"documented":[{"label":"Espesor del muro","value":0.1,"unit":"m","source":"ARQ-SB-20260710 · Arquitectura A103 / p. 5; A301Cuadro de materiales ","status":"documentado"}],"geometry":[{"label":"Dimensiones de la caja local del elemento (X, Y, Z)","value":"3.8 × 0.1 × 1.5","unit":"m","source":"Malla triangulada del elemento en ejes locales del edificio","status":"derivado"},{"label":"Cota mínima absoluta de la malla","value":290.35,"unit":"m","source":"Malla de proyecto y origen altimétrico 285 m","status":"derivado"},{"label":"Cota máxima absoluta de la malla","value":291.85,"unit":"m","source":"Malla de proyecto y origen altimétrico 285 m","status":"derivado"},{"label":"Volumen geométrico bruto","value":0.57,"unit":"m³","source":"Malla cerrada del elemento","status":"derivado"}],"notes":["Las dimensiones documentadas proceden de anotaciones o cuadros; la caja y el volumen se calculan a partir de la malla.","El volumen es exclusivamente geométrico y bruto; no representa una medición neta de material ni una cantidad de compra."]} | {"documentId":"ARQ-SB-20260710","title":"Planos de arquitectura de la sala de bombas contra incendios","date":"2026-07-10","sheet":"Arquitectura A103 / p. 5; A301Cuadro de materiales "} | ["Envolvente exterior controlada por la planta de arquitectura; no se han modelado individualmente todas las capas de acabado.","Registro de líneas del PDF general con envolvente de 10,2 × 8,2 m. Estimación de trabajo de implantación de ±0,15 m, pendiente de CAD nativo; no constituye una precisión topográfica garantizada."] | {"horizontalStatus":"derivado","verticalStatus":"derivado","baseElevationM":286.25,"note":"Registro de líneas del PDF general con envolvente de 10,2 × 8,2 m. Estimación de trabajo de implantación de ±0,15 m, pendiente de CAD nativo; no constituye una precisión topográfica garantizada."} | {"Pset_WallCommon":{"IsExternal":{"value":true,"source":"ARQ-SB-20260710 · A101, A103 y alzados; elemento de la envolvente exterior identificada en planta","status":"known"}}} | {"boundingBoxM":{"min":[11.28627,25.840421,5.35],"max":[15.064478,26.457064,6.85]},"extentsM":[3.778208,0.616643,1.5],"meshSurfaceM2":12.46,"meshVolumeM3":0.57,"closedSolid":true,"basis":"Geometría triangulada releída del IFC; envolventes y magnitudes no contractuales."} | {"material":true,"document":true,"quantities":true,"containerGuid":"0Wh59pm9LO_einrwiq6Es1","containerName":"Planta baja"} | {"id":"architecture","name":"Arquitectura"} | {"profileId":"sandwich_panel","name":"Panel sándwich · chapa gris clara","materialName":"Panel sándwich de acero con núcleo de lana de roca","physicalMaterialStatus":"known","physicalMaterialSource":"ARQ-SB-20260710 · Arquitectura A103 / p. 5; A301Cuadro de materiales ; ARQ-OF-20260710 · A301 / p. 16, bloque correspondiente a la sala de bombas","appearanceStatus":"criterio_visual","appearanceBasis":"Interpretación visual del material documental; el acabado, tono y parámetros PBR no son una especificación contractual.","note":"La apariencia gráfica no modifica ni confirma la especificación física del material."} | {"elementId":"pump_house_0014","ifcGuid":"2j4gBKAk9GPeDVGVtNdzwF","ifcClass":"IfcWall","buildingId":"pump_house","buildingName":"Sala de bombas contra incendios","sourceDocumentId":"ARQ-SB-20260710","sourceRepresentationKind":"documentary_mesh"} | {"layerId":"architecture","layerName":"Arquitectura","role":"Muro","basis":"Clasificación por función del elemento; no modifica las especificaciones documentales."} | architecture | {"profileId":"sandwich_panel","name":"Panel sándwich · chapa gris clara","status":"criterio_visual","basis":"Interpretación visual del material documental; el acabado, tono y parámetros PBR no son una especificación contractual.","physicalMaterialUnchanged":true} | ARQ-SB-20260710 · Arquitectura A103 / p. 5; A301Cuadro de materiales | Dimensiones contrastadas con los planos; reconstrucción geométrica a partir de documentación de diseño. | 0.1 | Muros segmentados con huecos reales para puertas y ventanas. | Envolvente exterior controlada por la planta de arquitectura; no se han modelado individualmente todas las capas de acabado. | Registro de líneas del PDF general con envolvente de 10,2 × 8,2 m. Estimación de trabajo de implantación de ±0,15 m, pendiente de CAD nativo; no constituye una precisión topográfica garantizada. | Arquitectura | ARQ-SB-20260710 · Arquitectura A103 / p. 5; A301Cuadro de materiales ; ARQ-OF-20260710 · A301 / p. 16, bloque correspondiente a la sala de bombas | 286.25 | Arquitectura | Panel sándwich · chapa gris clara | sandwich_panel | [0.85098,0.87451,0.87451] | 0.48 | 0.28 | Interpretación visual del material documental; el acabado, tono y parámetros PBR no son una especificación contractual. | Arquitectura; BIM · Arquitectura
Sala de bombas contra incendios · Panel sándwich de fachada con núcleo de lana de roca · eje A · tramo 09 | Planos de arquitectura de la sala de bombas contra incendios; Planos de arquitectura de la sala de bombas contra incendios | Panel sándwich de acero con núcleo de lana de roca | 1.2 × 0.1 × 0.3 | 287.45 | 287.75 | 0.036 | pump_house_0015 | yes | 1.20244 | 0.262513 | 0.3 | 1.02 | 0.0360002 | pump_house | Sala de bombas contra incendios | {"name":"Panel sándwich de acero con núcleo de lana de roca","source":"ARQ-SB-20260710 · Arquitectura A103 / p. 5; A301Cuadro de materiales ; ARQ-OF-20260710 · A301 / p. 16, bloque correspondiente a la sala de bombas","status":"known"} | {"documented":[{"label":"Espesor del muro","value":0.1,"unit":"m","source":"ARQ-SB-20260710 · Arquitectura A103 / p. 5; A301Cuadro de materiales ","status":"documentado"}],"geometry":[{"label":"Dimensiones de la caja local del elemento (X, Y, Z)","value":"1.2 × 0.1 × 0.3","unit":"m","source":"Malla triangulada del elemento en ejes locales del edificio","status":"derivado"},{"label":"Cota mínima absoluta de la malla","value":287.45,"unit":"m","source":"Malla de proyecto y origen altimétrico 285 m","status":"derivado"},{"label":"Cota máxima absoluta de la malla","value":287.75,"unit":"m","source":"Malla de proyecto y origen altimétrico 285 m","status":"derivado"},{"label":"Volumen geométrico bruto","value":0.036,"unit":"m³","source":"Malla cerrada del elemento","status":"derivado"}],"notes":["Las dimensiones documentadas proceden de anotaciones o cuadros; la caja y el volumen se calculan a partir de la malla.","El volumen es exclusivamente geométrico y bruto; no representa una medición neta de material ni una cantidad de compra."]} | {"documentId":"ARQ-SB-20260710","title":"Planos de arquitectura de la sala de bombas contra incendios","date":"2026-07-10","sheet":"Arquitectura A103 / p. 5; A301Cuadro de materiales "} | ["Envolvente exterior controlada por la planta de arquitectura; no se han modelado individualmente todas las capas de acabado.","Registro de líneas del PDF general con envolvente de 10,2 × 8,2 m. Estimación de trabajo de implantación de ±0,15 m, pendiente de CAD nativo; no constituye una precisión topográfica garantizada."] | {"horizontalStatus":"derivado","verticalStatus":"derivado","baseElevationM":286.25,"note":"Registro de líneas del PDF general con envolvente de 10,2 × 8,2 m. Estimación de trabajo de implantación de ±0,15 m, pendiente de CAD nativo; no constituye una precisión topográfica garantizada."} | {"Pset_WallCommon":{"IsExternal":{"value":true,"source":"ARQ-SB-20260710 · A101, A103 y alzados; elemento de la envolvente exterior identificada en planta","status":"known"}}} | {"boundingBoxM":{"min":[15.050857,25.676976,2.45],"max":[16.253295,25.939489,2.75]},"extentsM":[1.202438,0.262513,0.3],"meshSurfaceM2":1.020001,"meshVolumeM3":0.036,"closedSolid":true,"basis":"Geometría triangulada releída del IFC; envolventes y magnitudes no contractuales."} | {"material":true,"document":true,"quantities":true,"containerGuid":"0Wh59pm9LO_einrwiq6Es1","containerName":"Planta baja"} | {"id":"architecture","name":"Arquitectura"} | {"profileId":"sandwich_panel","name":"Panel sándwich · chapa gris clara","materialName":"Panel sándwich de acero con núcleo de lana de roca","physicalMaterialStatus":"known","physicalMaterialSource":"ARQ-SB-20260710 · Arquitectura A103 / p. 5; A301Cuadro de materiales ; ARQ-OF-20260710 · A301 / p. 16, bloque correspondiente a la sala de bombas","appearanceStatus":"criterio_visual","appearanceBasis":"Interpretación visual del material documental; el acabado, tono y parámetros PBR no son una especificación contractual.","note":"La apariencia gráfica no modifica ni confirma la especificación física del material."} | {"elementId":"pump_house_0015","ifcGuid":"3p02OOzwnUkRFhbAreHlvk","ifcClass":"IfcWall","buildingId":"pump_house","buildingName":"Sala de bombas contra incendios","sourceDocumentId":"ARQ-SB-20260710","sourceRepresentationKind":"documentary_mesh"} | {"layerId":"architecture","layerName":"Arquitectura","role":"Muro","basis":"Clasificación por función del elemento; no modifica las especificaciones documentales."} | architecture | {"profileId":"sandwich_panel","name":"Panel sándwich · chapa gris clara","status":"criterio_visual","basis":"Interpretación visual del material documental; el acabado, tono y parámetros PBR no son una especificación contractual.","physicalMaterialUnchanged":true} | ARQ-SB-20260710 · Arquitectura A103 / p. 5; A301Cuadro de materiales | Dimensiones contrastadas con los planos; reconstrucción geométrica a partir de documentación de diseño. | 0.1 | Muros segmentados con huecos reales para puertas y ventanas. | Envolvente exterior controlada por la planta de arquitectura; no se han modelado individualmente todas las capas de acabado. | Registro de líneas del PDF general con envolvente de 10,2 × 8,2 m. Estimación de trabajo de implantación de ±0,15 m, pendiente de CAD nativo; no constituye una precisión topográfica garantizada. | Arquitectura | ARQ-SB-20260710 · Arquitectura A103 / p. 5; A301Cuadro de materiales ; ARQ-OF-20260710 · A301 / p. 16, bloque correspondiente a la sala de bombas | 286.25 | Arquitectura | Panel sándwich · chapa gris clara | sandwich_panel | [0.85098,0.87451,0.87451] | 0.48 | 0.28 | Interpretación visual del material documental; el acabado, tono y parámetros PBR no son una especificación contractual. | Arquitectura; BIM · Arquitectura
Sala de bombas contra incendios · Panel sándwich de fachada con núcleo de lana de roca · eje A · tramo 10 | Planos de arquitectura de la sala de bombas contra incendios; Planos de arquitectura de la sala de bombas contra incendios | Panel sándwich de acero con núcleo de lana de roca | 1.2 × 0.1 × 1.5 | 290.35 | 291.85 | 0.18 | pump_house_0016 | yes | 1.20244 | 0.262513 | 1.5 | 4.14 | 0.180001 | pump_house | Sala de bombas contra incendios | {"name":"Panel sándwich de acero con núcleo de lana de roca","source":"ARQ-SB-20260710 · Arquitectura A103 / p. 5; A301Cuadro de materiales ; ARQ-OF-20260710 · A301 / p. 16, bloque correspondiente a la sala de bombas","status":"known"} | {"documented":[{"label":"Espesor del muro","value":0.1,"unit":"m","source":"ARQ-SB-20260710 · Arquitectura A103 / p. 5; A301Cuadro de materiales ","status":"documentado"}],"geometry":[{"label":"Dimensiones de la caja local del elemento (X, Y, Z)","value":"1.2 × 0.1 × 1.5","unit":"m","source":"Malla triangulada del elemento en ejes locales del edificio","status":"derivado"},{"label":"Cota mínima absoluta de la malla","value":290.35,"unit":"m","source":"Malla de proyecto y origen altimétrico 285 m","status":"derivado"},{"label":"Cota máxima absoluta de la malla","value":291.85,"unit":"m","source":"Malla de proyecto y origen altimétrico 285 m","status":"derivado"},{"label":"Volumen geométrico bruto","value":0.18,"unit":"m³","source":"Malla cerrada del elemento","status":"derivado"}],"notes":["Las dimensiones documentadas proceden de anotaciones o cuadros; la caja y el volumen se calculan a partir de la malla.","El volumen es exclusivamente geométrico y bruto; no representa una medición neta de material ni una cantidad de compra."]} | {"documentId":"ARQ-SB-20260710","title":"Planos de arquitectura de la sala de bombas contra incendios","date":"2026-07-10","sheet":"Arquitectura A103 / p. 5; A301Cuadro de materiales "} | ["Envolvente exterior controlada por la planta de arquitectura; no se han modelado individualmente todas las capas de acabado.","Registro de líneas del PDF general con envolvente de 10,2 × 8,2 m. Estimación de trabajo de implantación de ±0,15 m, pendiente de CAD nativo; no constituye una precisión topográfica garantizada."] | {"horizontalStatus":"derivado","verticalStatus":"derivado","baseElevationM":286.25,"note":"Registro de líneas del PDF general con envolvente de 10,2 × 8,2 m. Estimación de trabajo de implantación de ±0,15 m, pendiente de CAD nativo; no constituye una precisión topográfica garantizada."} | {"Pset_WallCommon":{"IsExternal":{"value":true,"source":"ARQ-SB-20260710 · A101, A103 y alzados; elemento de la envolvente exterior identificada en planta","status":"known"}}} | {"boundingBoxM":{"min":[15.050857,25.676976,5.35],"max":[16.253295,25.939489,6.85]},"extentsM":[1.202438,0.262513,1.5],"meshSurfaceM2":4.140003,"meshVolumeM3":0.180001,"closedSolid":true,"basis":"Geometría triangulada releída del IFC; envolventes y magnitudes no contractuales."} | {"material":true,"document":true,"quantities":true,"containerGuid":"0Wh59pm9LO_einrwiq6Es1","containerName":"Planta baja"} | {"id":"architecture","name":"Arquitectura"} | {"profileId":"sandwich_panel","name":"Panel sándwich · chapa gris clara","materialName":"Panel sándwich de acero con núcleo de lana de roca","physicalMaterialStatus":"known","physicalMaterialSource":"ARQ-SB-20260710 · Arquitectura A103 / p. 5; A301Cuadro de materiales ; ARQ-OF-20260710 · A301 / p. 16, bloque correspondiente a la sala de bombas","appearanceStatus":"criterio_visual","appearanceBasis":"Interpretación visual del material documental; el acabado, tono y parámetros PBR no son una especificación contractual.","note":"La apariencia gráfica no modifica ni confirma la especificación física del material."} | {"elementId":"pump_house_0016","ifcGuid":"24FhTm6yLO7vgqZE1y_asq","ifcClass":"IfcWall","buildingId":"pump_house","buildingName":"Sala de bombas contra incendios","sourceDocumentId":"ARQ-SB-20260710","sourceRepresentationKind":"documentary_mesh"} | {"layerId":"architecture","layerName":"Arquitectura","role":"Muro","basis":"Clasificación por función del elemento; no modifica las especificaciones documentales."} | architecture | {"profileId":"sandwich_panel","name":"Panel sándwich · chapa gris clara","status":"criterio_visual","basis":"Interpretación visual del material documental; el acabado, tono y parámetros PBR no son una especificación contractual.","physicalMaterialUnchanged":true} | ARQ-SB-20260710 · Arquitectura A103 / p. 5; A301Cuadro de materiales | Dimensiones contrastadas con los planos; reconstrucción geométrica a partir de documentación de diseño. | 0.1 | Muros segmentados con huecos reales para puertas y ventanas. | Envolvente exterior controlada por la planta de arquitectura; no se han modelado individualmente todas las capas de acabado. | Registro de líneas del PDF general con envolvente de 10,2 × 8,2 m. Estimación de trabajo de implantación de ±0,15 m, pendiente de CAD nativo; no constituye una precisión topográfica garantizada. | Arquitectura | ARQ-SB-20260710 · Arquitectura A103 / p. 5; A301Cuadro de materiales ; ARQ-OF-20260710 · A301 / p. 16, bloque correspondiente a la sala de bombas | 286.25 | Arquitectura | Panel sándwich · chapa gris clara | sandwich_panel | [0.85098,0.87451,0.87451] | 0.48 | 0.28 | Interpretación visual del material documental; el acabado, tono y parámetros PBR no son una especificación contractual. | Arquitectura; BIM · Arquitectura
Sala de bombas contra incendios · Panel sándwich de fachada con núcleo de lana de roca · eje A · tramo 11 | Planos de arquitectura de la sala de bombas contra incendios; Planos de arquitectura de la sala de bombas contra incendios | Panel sándwich de acero con núcleo de lana de roca | 2 × 0.1 × 0.3 | 287.45 | 287.75 | 0.06 | pump_house_0017 | yes | 1.99498 | 0.371476 | 0.3 | 1.66 | 0.0600003 | pump_house | Sala de bombas contra incendios | {"name":"Panel sándwich de acero con núcleo de lana de roca","source":"ARQ-SB-20260710 · Arquitectura A103 / p. 5; A301Cuadro de materiales ; ARQ-OF-20260710 · A301 / p. 16, bloque correspondiente a la sala de bombas","status":"known"} | {"documented":[{"label":"Espesor del muro","value":0.1,"unit":"m","source":"ARQ-SB-20260710 · Arquitectura A103 / p. 5; A301Cuadro de materiales ","status":"documentado"}],"geometry":[{"label":"Dimensiones de la caja local del elemento (X, Y, Z)","value":"2 × 0.1 × 0.3","unit":"m","source":"Malla triangulada del elemento en ejes locales del edificio","status":"derivado"},{"label":"Cota mínima absoluta de la malla","value":287.45,"unit":"m","source":"Malla de proyecto y origen altimétrico 285 m","status":"derivado"},{"label":"Cota máxima absoluta de la malla","value":287.75,"unit":"m","source":"Malla de proyecto y origen altimétrico 285 m","status":"derivado"},{"label":"Volumen geométrico bruto","value":0.06,"unit":"m³","source":"Malla cerrada del elemento","status":"derivado"}],"notes":["Las dimensiones documentadas proceden de anotaciones o cuadros; la caja y el volumen se calculan a partir de la malla.","El volumen es exclusivamente geométrico y bruto; no representa una medición neta de material ni una cantidad de compra."]} | {"documentId":"ARQ-SB-20260710","title":"Planos de arquitectura de la sala de bombas contra incendios","date":"2026-07-10","sheet":"Arquitectura A103 / p. 5; A301Cuadro de materiales "} | ["Envolvente exterior controlada por la planta de arquitectura; no se han modelado individualmente todas las capas de acabado.","Registro de líneas del PDF general con envolvente de 10,2 × 8,2 m. Estimación de trabajo de implantación de ±0,15 m, pendiente de CAD nativo; no constituye una precisión topográfica garantizada."] | {"horizontalStatus":"derivado","verticalStatus":"derivado","baseElevationM":286.25,"note":"Registro de líneas del PDF general con envolvente de 10,2 × 8,2 m. Estimación de trabajo de implantación de ±0,15 m, pendiente de CAD nativo; no constituye una precisión topográfica garantizada."} | {"Pset_WallCommon":{"IsExternal":{"value":true,"source":"ARQ-SB-20260710 · A101, A103 y alzados; elemento de la envolvente exterior identificada en planta","status":"known"}}} | {"boundingBoxM":{"min":[16.239674,25.404569,2.45],"max":[18.234656,25.776045,2.75]},"extentsM":[1.994982,0.371476,0.3],"meshSurfaceM2":1.660002,"meshVolumeM3":0.06,"closedSolid":true,"basis":"Geometría triangulada releída del IFC; envolventes y magnitudes no contractuales."} | {"material":true,"document":true,"quantities":true,"containerGuid":"0Wh59pm9LO_einrwiq6Es1","containerName":"Planta baja"} | {"id":"architecture","name":"Arquitectura"} | {"profileId":"sandwich_panel","name":"Panel sándwich · chapa gris clara","materialName":"Panel sándwich de acero con núcleo de lana de roca","physicalMaterialStatus":"known","physicalMaterialSource":"ARQ-SB-20260710 · Arquitectura A103 / p. 5; A301Cuadro de materiales ; ARQ-OF-20260710 · A301 / p. 16, bloque correspondiente a la sala de bombas","appearanceStatus":"criterio_visual","appearanceBasis":"Interpretación visual del material documental; el acabado, tono y parámetros PBR no son una especificación contractual.","note":"La apariencia gráfica no modifica ni confirma la especificación física del material."} | {"elementId":"pump_house_0017","ifcGuid":"0Grmg9HknQK9eZeT1DVIUP","ifcClass":"IfcWall","buildingId":"pump_house","buildingName":"Sala de bombas contra incendios","sourceDocumentId":"ARQ-SB-20260710","sourceRepresentationKind":"documentary_mesh"} | {"layerId":"architecture","layerName":"Arquitectura","role":"Muro","basis":"Clasificación por función del elemento; no modifica las especificaciones documentales."} | architecture | {"profileId":"sandwich_panel","name":"Panel sándwich · chapa gris clara","status":"criterio_visual","basis":"Interpretación visual del material documental; el acabado, tono y parámetros PBR no son una especificación contractual.","physicalMaterialUnchanged":true} | ARQ-SB-20260710 · Arquitectura A103 / p. 5; A301Cuadro de materiales | Dimensiones contrastadas con los planos; reconstrucción geométrica a partir de documentación de diseño. | 0.1 | Muros segmentados con huecos reales para puertas y ventanas. | Envolvente exterior controlada por la planta de arquitectura; no se han modelado individualmente todas las capas de acabado. | Registro de líneas del PDF general con envolvente de 10,2 × 8,2 m. Estimación de trabajo de implantación de ±0,15 m, pendiente de CAD nativo; no constituye una precisión topográfica garantizada. | Arquitectura | ARQ-SB-20260710 · Arquitectura A103 / p. 5; A301Cuadro de materiales ; ARQ-OF-20260710 · A301 / p. 16, bloque correspondiente a la sala de bombas | 286.25 | Arquitectura | Panel sándwich · chapa gris clara | sandwich_panel | [0.85098,0.87451,0.87451] | 0.48 | 0.28 | Interpretación visual del material documental; el acabado, tono y parámetros PBR no son una especificación contractual. | Arquitectura; BIM · Arquitectura
Sala de bombas contra incendios · Panel sándwich de fachada con núcleo de lana de roca · eje A · tramo 12 | Planos de arquitectura de la sala de bombas contra incendios; Planos de arquitectura de la sala de bombas contra incendios | Panel sándwich de acero con núcleo de lana de roca | 2 × 0.1 × 2.6 | 287.75 | 290.35 | 0.52 | pump_house_0018 | yes | 1.99498 | 0.371476 | 2.6 | 11.32 | 0.520002 | pump_house | Sala de bombas contra incendios | {"name":"Panel sándwich de acero con núcleo de lana de roca","source":"ARQ-SB-20260710 · Arquitectura A103 / p. 5; A301Cuadro de materiales ; ARQ-OF-20260710 · A301 / p. 16, bloque correspondiente a la sala de bombas","status":"known"} | {"documented":[{"label":"Espesor del muro","value":0.1,"unit":"m","source":"ARQ-SB-20260710 · Arquitectura A103 / p. 5; A301Cuadro de materiales ","status":"documentado"}],"geometry":[{"label":"Dimensiones de la caja local del elemento (X, Y, Z)","value":"2 × 0.1 × 2.6","unit":"m","source":"Malla triangulada del elemento en ejes locales del edificio","status":"derivado"},{"label":"Cota mínima absoluta de la malla","value":287.75,"unit":"m","source":"Malla de proyecto y origen altimétrico 285 m","status":"derivado"},{"label":"Cota máxima absoluta de la malla","value":290.35,"unit":"m","source":"Malla de proyecto y origen altimétrico 285 m","status":"derivado"},{"label":"Volumen geométrico bruto","value":0.52,"unit":"m³","source":"Malla cerrada del elemento","status":"derivado"}],"notes":["Las dimensiones documentadas proceden de anotaciones o cuadros; la caja y el volumen se calculan a partir de la malla.","El volumen es exclusivamente geométrico y bruto; no representa una medición neta de material ni una cantidad de compra."]} | {"documentId":"ARQ-SB-20260710","title":"Planos de arquitectura de la sala de bombas contra incendios","date":"2026-07-10","sheet":"Arquitectura A103 / p. 5; A301Cuadro de materiales "} | ["Envolvente exterior controlada por la planta de arquitectura; no se han modelado individualmente todas las capas de acabado.","Registro de líneas del PDF general con envolvente de 10,2 × 8,2 m. Estimación de trabajo de implantación de ±0,15 m, pendiente de CAD nativo; no constituye una precisión topográfica garantizada."] | {"horizontalStatus":"derivado","verticalStatus":"derivado","baseElevationM":286.25,"note":"Registro de líneas del PDF general con envolvente de 10,2 × 8,2 m. Estimación de trabajo de implantación de ±0,15 m, pendiente de CAD nativo; no constituye una precisión topográfica garantizada."} | {"Pset_WallCommon":{"IsExternal":{"value":true,"source":"ARQ-SB-20260710 · A101, A103 y alzados; elemento de la envolvente exterior identificada en planta","status":"known"}}} | {"boundingBoxM":{"min":[16.239674,25.404569,2.75],"max":[18.234656,25.776045,5.35]},"extentsM":[1.994982,0.371476,2.6],"meshSurfaceM2":11.320003,"meshVolumeM3":0.520002,"closedSolid":true,"basis":"Geometría triangulada releída del IFC; envolventes y magnitudes no contractuales."} | {"material":true,"document":true,"quantities":true,"containerGuid":"0Wh59pm9LO_einrwiq6Es1","containerName":"Planta baja"} | {"id":"architecture","name":"Arquitectura"} | {"profileId":"sandwich_panel","name":"Panel sándwich · chapa gris clara","materialName":"Panel sándwich de acero con núcleo de lana de roca","physicalMaterialStatus":"known","physicalMaterialSource":"ARQ-SB-20260710 · Arquitectura A103 / p. 5; A301Cuadro de materiales ; ARQ-OF-20260710 · A301 / p. 16, bloque correspondiente a la sala de bombas","appearanceStatus":"criterio_visual","appearanceBasis":"Interpretación visual del material documental; el acabado, tono y parámetros PBR no son una especificación contractual.","note":"La apariencia gráfica no modifica ni confirma la especificación física del material."} | {"elementId":"pump_house_0018","ifcGuid":"07gKK0DzvOXABA$dTl2Jni","ifcClass":"IfcWall","buildingId":"pump_house","buildingName":"Sala de bombas contra incendios","sourceDocumentId":"ARQ-SB-20260710","sourceRepresentationKind":"documentary_mesh"} | {"layerId":"architecture","layerName":"Arquitectura","role":"Muro","basis":"Clasificación por función del elemento; no modifica las especificaciones documentales."} | architecture | {"profileId":"sandwich_panel","name":"Panel sándwich · chapa gris clara","status":"criterio_visual","basis":"Interpretación visual del material documental; el acabado, tono y parámetros PBR no son una especificación contractual.","physicalMaterialUnchanged":true} | ARQ-SB-20260710 · Arquitectura A103 / p. 5; A301Cuadro de materiales | Dimensiones contrastadas con los planos; reconstrucción geométrica a partir de documentación de diseño. | 0.1 | Muros segmentados con huecos reales para puertas y ventanas. | Envolvente exterior controlada por la planta de arquitectura; no se han modelado individualmente todas las capas de acabado. | Registro de líneas del PDF general con envolvente de 10,2 × 8,2 m. Estimación de trabajo de implantación de ±0,15 m, pendiente de CAD nativo; no constituye una precisión topográfica garantizada. | Arquitectura | ARQ-SB-20260710 · Arquitectura A103 / p. 5; A301Cuadro de materiales ; ARQ-OF-20260710 · A301 / p. 16, bloque correspondiente a la sala de bombas | 286.25 | Arquitectura | Panel sándwich · chapa gris clara | sandwich_panel | [0.85098,0.87451,0.87451] | 0.48 | 0.28 | Interpretación visual del material documental; el acabado, tono y parámetros PBR no son una especificación contractual. | Arquitectura; BIM · Arquitectura
Sala de bombas contra incendios · Panel sándwich de fachada con núcleo de lana de roca · eje A · tramo 13 | Planos de arquitectura de la sala de bombas contra incendios; Planos de arquitectura de la sala de bombas contra incendios | Panel sándwich de acero con núcleo de lana de roca | 2 × 0.1 × 1.5 | 290.35 | 291.85 | 0.3 | pump_house_0019 | yes | 1.99498 | 0.371476 | 1.5 | 6.7 | 0.300001 | pump_house | Sala de bombas contra incendios | {"name":"Panel sándwich de acero con núcleo de lana de roca","source":"ARQ-SB-20260710 · Arquitectura A103 / p. 5; A301Cuadro de materiales ; ARQ-OF-20260710 · A301 / p. 16, bloque correspondiente a la sala de bombas","status":"known"} | {"documented":[{"label":"Espesor del muro","value":0.1,"unit":"m","source":"ARQ-SB-20260710 · Arquitectura A103 / p. 5; A301Cuadro de materiales ","status":"documentado"}],"geometry":[{"label":"Dimensiones de la caja local del elemento (X, Y, Z)","value":"2 × 0.1 × 1.5","unit":"m","source":"Malla triangulada del elemento en ejes locales del edificio","status":"derivado"},{"label":"Cota mínima absoluta de la malla","value":290.35,"unit":"m","source":"Malla de proyecto y origen altimétrico 285 m","status":"derivado"},{"label":"Cota máxima absoluta de la malla","value":291.85,"unit":"m","source":"Malla de proyecto y origen altimétrico 285 m","status":"derivado"},{"label":"Volumen geométrico bruto","value":0.3,"unit":"m³","source":"Malla cerrada del elemento","status":"derivado"}],"notes":["Las dimensiones documentadas proceden de anotaciones o cuadros; la caja y el volumen se calculan a partir de la malla.","El volumen es exclusivamente geométrico y bruto; no representa una medición neta de material ni una cantidad de compra."]} | {"documentId":"ARQ-SB-20260710","title":"Planos de arquitectura de la sala de bombas contra incendios","date":"2026-07-10","sheet":"Arquitectura A103 / p. 5; A301Cuadro de materiales "} | ["Envolvente exterior controlada por la planta de arquitectura; no se han modelado individualmente todas las capas de acabado.","Registro de líneas del PDF general con envolvente de 10,2 × 8,2 m. Estimación de trabajo de implantación de ±0,15 m, pendiente de CAD nativo; no constituye una precisión topográfica garantizada."] | {"horizontalStatus":"derivado","verticalStatus":"derivado","baseElevationM":286.25,"note":"Registro de líneas del PDF general con envolvente de 10,2 × 8,2 m. Estimación de trabajo de implantación de ±0,15 m, pendiente de CAD nativo; no constituye una precisión topográfica garantizada."} | {"Pset_WallCommon":{"IsExternal":{"value":true,"source":"ARQ-SB-20260710 · A101, A103 y alzados; elemento de la envolvente exterior identificada en planta","status":"known"}}} | {"boundingBoxM":{"min":[16.239674,25.404569,5.35],"max":[18.234656,25.776045,6.85]},"extentsM":[1.994982,0.371476,1.5],"meshSurfaceM2":6.700002,"meshVolumeM3":0.300001,"closedSolid":true,"basis":"Geometría triangulada releída del IFC; envolventes y magnitudes no contractuales."} | {"material":true,"document":true,"quantities":true,"containerGuid":"0Wh59pm9LO_einrwiq6Es1","containerName":"Planta baja"} | {"id":"architecture","name":"Arquitectura"} | {"profileId":"sandwich_panel","name":"Panel sándwich · chapa gris clara","materialName":"Panel sándwich de acero con núcleo de lana de roca","physicalMaterialStatus":"known","physicalMaterialSource":"ARQ-SB-20260710 · Arquitectura A103 / p. 5; A301Cuadro de materiales ; ARQ-OF-20260710 · A301 / p. 16, bloque correspondiente a la sala de bombas","appearanceStatus":"criterio_visual","appearanceBasis":"Interpretación visual del material documental; el acabado, tono y parámetros PBR no son una especificación contractual.","note":"La apariencia gráfica no modifica ni confirma la especificación física del material."} | {"elementId":"pump_house_0019","ifcGuid":"2VjQKmOM1VEeKXUz7WXGkA","ifcClass":"IfcWall","buildingId":"pump_house","buildingName":"Sala de bombas contra incendios","sourceDocumentId":"ARQ-SB-20260710","sourceRepresentationKind":"documentary_mesh"} | {"layerId":"architecture","layerName":"Arquitectura","role":"Muro","basis":"Clasificación por función del elemento; no modifica las especificaciones documentales."} | architecture | {"profileId":"sandwich_panel","name":"Panel sándwich · chapa gris clara","status":"criterio_visual","basis":"Interpretación visual del material documental; el acabado, tono y parámetros PBR no son una especificación contractual.","physicalMaterialUnchanged":true} | ARQ-SB-20260710 · Arquitectura A103 / p. 5; A301Cuadro de materiales | Dimensiones contrastadas con los planos; reconstrucción geométrica a partir de documentación de diseño. | 0.1 | Muros segmentados con huecos reales para puertas y ventanas. | Envolvente exterior controlada por la planta de arquitectura; no se han modelado individualmente todas las capas de acabado. | Registro de líneas del PDF general con envolvente de 10,2 × 8,2 m. Estimación de trabajo de implantación de ±0,15 m, pendiente de CAD nativo; no constituye una precisión topográfica garantizada. | Arquitectura | ARQ-SB-20260710 · Arquitectura A103 / p. 5; A301Cuadro de materiales ; ARQ-OF-20260710 · A301 / p. 16, bloque correspondiente a la sala de bombas | 286.25 | Arquitectura | Panel sándwich · chapa gris clara | sandwich_panel | [0.85098,0.87451,0.87451] | 0.48 | 0.28 | Interpretación visual del material documental; el acabado, tono y parámetros PBR no son una especificación contractual. | Arquitectura; BIM · Arquitectura
Sala de bombas contra incendios · Zócalo de hormigón · eje B · tramo 01 | Planos de arquitectura de la sala de bombas contra incendios; Planos de arquitectura de la sala de bombas contra incendios | Hormigón prefabricado macizo | 2.4 × 0.2 × 1.2 | 286.25 | 287.45 | 0.576 | pump_house_0020 | yes | 2.40487 | 0.525025 | 1.2 | 7.2 | 0.576 | pump_house | Sala de bombas contra incendios | {"name":"Hormigón prefabricado macizo","source":"ARQ-SB-20260710 · Arquitectura A103 / p. 5; Estructura A201 / p. 4","status":"known"} | {"documented":[{"label":"Espesor del muro","value":0.2,"unit":"m","source":"ARQ-SB-20260710 · Arquitectura A103 / p. 5; Estructura A201 / p. 4","status":"documentado"}],"geometry":[{"label":"Dimensiones de la caja local del elemento (X, Y, Z)","value":"2.4 × 0.2 × 1.2","unit":"m","source":"Malla triangulada del elemento en ejes locales del edificio","status":"derivado"},{"label":"Cota mínima absoluta de la malla","value":286.25,"unit":"m","source":"Malla de proyecto y origen altimétrico 285 m","status":"derivado"},{"label":"Cota máxima absoluta de la malla","value":287.45,"unit":"m","source":"Malla de proyecto y origen altimétrico 285 m","status":"derivado"},{"label":"Volumen geométrico bruto","value":0.576,"unit":"m³","source":"Malla cerrada del elemento","status":"derivado"}],"notes":["Las dimensiones documentadas proceden de anotaciones o cuadros; la caja y el volumen se calculan a partir de la malla.","El volumen es exclusivamente geométrico y bruto; no representa una medición neta de material ni una cantidad de compra."]} | {"documentId":"ARQ-SB-20260710","title":"Planos de arquitectura de la sala de bombas contra incendios","date":"2026-07-10","sheet":"Arquitectura A103 / p. 5; Estructura A201 / p. 4"} | ["Envolvente exterior controlada por la planta de arquitectura; no se han modelado individualmente todas las capas de acabado.","Registro de líneas del PDF general con envolvente de 10,2 × 8,2 m. Estimación de trabajo de implantación de ±0,15 m, pendiente de CAD nativo; no constituye una precisión topográfica garantizada."] | {"horizontalStatus":"derivado","verticalStatus":"derivado","baseElevationM":286.25,"note":"Registro de líneas del PDF general con envolvente de 10,2 × 8,2 m. Estimación de trabajo de implantación de ±0,15 m, pendiente de CAD nativo; no constituye una precisión topográfica garantizada."} | {"Pset_WallCommon":{"IsExternal":{"value":true,"source":"ARQ-SB-20260710 · A101, A103 y alzados; elemento de la envolvente exterior identificada en planta","status":"known"}}} | {"boundingBoxM":{"min":[9.205723,34.392406,1.25],"max":[11.610598,34.917431,2.45]},"extentsM":[2.404875,0.525025,1.2],"meshSurfaceM2":7.199999,"meshVolumeM3":0.576,"closedSolid":true,"basis":"Geometría triangulada releída del IFC; envolventes y magnitudes no contractuales."} | {"material":true,"document":true,"quantities":true,"containerGuid":"0Wh59pm9LO_einrwiq6Es1","containerName":"Planta baja"} | {"id":"architecture","name":"Arquitectura"} | {"profileId":"concrete_precast","name":"Hormigón prefabricado","materialName":"Hormigón prefabricado macizo","physicalMaterialStatus":"known","physicalMaterialSource":"ARQ-SB-20260710 · Arquitectura A103 / p. 5; Estructura A201 / p. 4","appearanceStatus":"criterio_visual","appearanceBasis":"Interpretación visual del material documental; el acabado, tono y parámetros PBR no son una especificación contractual.","note":"La apariencia gráfica no modifica ni confirma la especificación física del material."} | {"elementId":"pump_house_0020","ifcGuid":"3uy13g1yzMUeOXqJ2yhch3","ifcClass":"IfcWall","buildingId":"pump_house","buildingName":"Sala de bombas contra incendios","sourceDocumentId":"ARQ-SB-20260710","sourceRepresentationKind":"documentary_mesh"} | {"layerId":"architecture","layerName":"Arquitectura","role":"Muro","basis":"Clasificación por función del elemento; no modifica las especificaciones documentales."} | architecture | {"profileId":"concrete_precast","name":"Hormigón prefabricado","status":"criterio_visual","basis":"Interpretación visual del material documental; el acabado, tono y parámetros PBR no son una especificación contractual.","physicalMaterialUnchanged":true} | ARQ-SB-20260710 · Arquitectura A103 / p. 5; Estructura A201 / p. 4 | Dimensiones contrastadas con los planos; reconstrucción geométrica a partir de documentación de diseño. | 0.2 | Muros segmentados con huecos reales para puertas y ventanas. | Envolvente exterior controlada por la planta de arquitectura; no se han modelado individualmente todas las capas de acabado. | Registro de líneas del PDF general con envolvente de 10,2 × 8,2 m. Estimación de trabajo de implantación de ±0,15 m, pendiente de CAD nativo; no constituye una precisión topográfica garantizada. | Arquitectura | ARQ-SB-20260710 · Arquitectura A103 / p. 5; Estructura A201 / p. 4 | 286.25 | Arquitectura | Hormigón prefabricado | concrete_precast | [0.756863,0.752941,0.717647] | 0.86 | 0 | Interpretación visual del material documental; el acabado, tono y parámetros PBR no son una especificación contractual. | Arquitectura; BIM · Arquitectura
Sala de bombas contra incendios · Zócalo de hormigón · eje B · tramo 02 | Planos de arquitectura de la sala de bombas contra incendios; Planos de arquitectura de la sala de bombas contra incendios | Hormigón prefabricado macizo | 1 × 0.2 × 1.2 | 286.25 | 287.45 | 0.24 | pump_house_0021 | yes | 1.01792 | 0.33434 | 1.2 | 3.28 | 0.24 | pump_house | Sala de bombas contra incendios | {"name":"Hormigón prefabricado macizo","source":"ARQ-SB-20260710 · Arquitectura A103 / p. 5; Estructura A201 / p. 4","status":"known"} | {"documented":[{"label":"Espesor del muro","value":0.2,"unit":"m","source":"ARQ-SB-20260710 · Arquitectura A103 / p. 5; Estructura A201 / p. 4","status":"documentado"}],"geometry":[{"label":"Dimensiones de la caja local del elemento (X, Y, Z)","value":"1 × 0.2 × 1.2","unit":"m","source":"Malla triangulada del elemento en ejes locales del edificio","status":"derivado"},{"label":"Cota mínima absoluta de la malla","value":286.25,"unit":"m","source":"Malla de proyecto y origen altimétrico 285 m","status":"derivado"},{"label":"Cota máxima absoluta de la malla","value":287.45,"unit":"m","source":"Malla de proyecto y origen altimétrico 285 m","status":"derivado"},{"label":"Volumen geométrico bruto","value":0.24,"unit":"m³","source":"Malla cerrada del elemento","status":"derivado"}],"notes":["Las dimensiones documentadas proceden de anotaciones o cuadros; la caja y el volumen se calculan a partir de la malla.","El volumen es exclusivamente geométrico y bruto; no representa una medición neta de material ni una cantidad de compra."]} | {"documentId":"ARQ-SB-20260710","title":"Planos de arquitectura de la sala de bombas contra incendios","date":"2026-07-10","sheet":"Arquitectura A103 / p. 5; Estructura A201 / p. 4"} | ["Envolvente exterior controlada por la planta de arquitectura; no se han modelado individualmente todas las capas de acabado.","Registro de líneas del PDF general con envolvente de 10,2 × 8,2 m. Estimación de trabajo de implantación de ±0,15 m, pendiente de CAD nativo; no constituye una precisión topográfica garantizada."] | {"horizontalStatus":"derivado","verticalStatus":"derivado","baseElevationM":286.25,"note":"Registro de líneas del PDF general con envolvente de 10,2 × 8,2 m. Estimación de trabajo de implantación de ±0,15 m, pendiente de CAD nativo; no constituye una precisión topográfica garantizada."} | {"Pset_WallCommon":{"IsExternal":{"value":true,"source":"ARQ-SB-20260710 · A101, A103 y alzados; elemento de la envolvente exterior identificada en planta","status":"known"}}} | {"boundingBoxM":{"min":[15.54608,33.711386,1.25],"max":[16.564002,34.045726,2.45]},"extentsM":[1.017922,0.33434,1.2],"meshSurfaceM2":3.28,"meshVolumeM3":0.24,"closedSolid":true,"basis":"Geometría triangulada releída del IFC; envolventes y magnitudes no contractuales."} | {"material":true,"document":true,"quantities":true,"containerGuid":"0Wh59pm9LO_einrwiq6Es1","containerName":"Planta baja"} | {"id":"architecture","name":"Arquitectura"} | {"profileId":"concrete_precast","name":"Hormigón prefabricado","materialName":"Hormigón prefabricado macizo","physicalMaterialStatus":"known","physicalMaterialSource":"ARQ-SB-20260710 · Arquitectura A103 / p. 5; Estructura A201 / p. 4","appearanceStatus":"criterio_visual","appearanceBasis":"Interpretación visual del material documental; el acabado, tono y parámetros PBR no son una especificación contractual.","note":"La apariencia gráfica no modifica ni confirma la especificación física del material."} | {"elementId":"pump_house_0021","ifcGuid":"3m$AtyEO9R3P$CZHNhhU$A","ifcClass":"IfcWall","buildingId":"pump_house","buildingName":"Sala de bombas contra incendios","sourceDocumentId":"ARQ-SB-20260710","sourceRepresentationKind":"documentary_mesh"} | {"layerId":"architecture","layerName":"Arquitectura","role":"Muro","basis":"Clasificación por función del elemento; no modifica las especificaciones documentales."} | architecture | {"profileId":"concrete_precast","name":"Hormigón prefabricado","status":"criterio_visual","basis":"Interpretación visual del material documental; el acabado, tono y parámetros PBR no son una especificación contractual.","physicalMaterialUnchanged":true} | ARQ-SB-20260710 · Arquitectura A103 / p. 5; Estructura A201 / p. 4 | Dimensiones contrastadas con los planos; reconstrucción geométrica a partir de documentación de diseño. | 0.2 | Muros segmentados con huecos reales para puertas y ventanas. | Envolvente exterior controlada por la planta de arquitectura; no se han modelado individualmente todas las capas de acabado. | Registro de líneas del PDF general con envolvente de 10,2 × 8,2 m. Estimación de trabajo de implantación de ±0,15 m, pendiente de CAD nativo; no constituye una precisión topográfica garantizada. | Arquitectura | ARQ-SB-20260710 · Arquitectura A103 / p. 5; Estructura A201 / p. 4 | 286.25 | Arquitectura | Hormigón prefabricado | concrete_precast | [0.756863,0.752941,0.717647] | 0.86 | 0 | Interpretación visual del material documental; el acabado, tono y parámetros PBR no son una especificación contractual. | Arquitectura; BIM · Arquitectura
Sala de bombas contra incendios · Zócalo de hormigón · eje B · tramo 03 | Planos de arquitectura de la sala de bombas contra incendios; Planos de arquitectura de la sala de bombas contra incendios | Hormigón prefabricado macizo | 1.3 × 0.2 × 1.2 | 286.25 | 287.45 | 0.312 | pump_house_0022 | yes | 1.31513 | 0.375201 | 1.2 | 4.12 | 0.312 | pump_house | Sala de bombas contra incendios | {"name":"Hormigón prefabricado macizo","source":"ARQ-SB-20260710 · Arquitectura A103 / p. 5; Estructura A201 / p. 4","status":"known"} | {"documented":[{"label":"Espesor del muro","value":0.2,"unit":"m","source":"ARQ-SB-20260710 · Arquitectura A103 / p. 5; Estructura A201 / p. 4","status":"documentado"}],"geometry":[{"label":"Dimensiones de la caja local del elemento (X, Y, Z)","value":"1.3 × 0.2 × 1.2","unit":"m","source":"Malla triangulada del elemento en ejes locales del edificio","status":"derivado"},{"label":"Cota mínima absoluta de la malla","value":286.25,"unit":"m","source":"Malla de proyecto y origen altimétrico 285 m","status":"derivado"},{"label":"Cota máxima absoluta de la malla","value":287.45,"unit":"m","source":"Malla de proyecto y origen altimétrico 285 m","status":"derivado"},{"label":"Volumen geométrico bruto","value":0.312,"unit":"m³","source":"Malla cerrada del elemento","status":"derivado"}],"notes":["Las dimensiones documentadas proceden de anotaciones o cuadros; la caja y el volumen se calculan a partir de la malla.","El volumen es exclusivamente geométrico y bruto; no representa una medición neta de material ni una cantidad de compra."]} | {"documentId":"ARQ-SB-20260710","title":"Planos de arquitectura de la sala de bombas contra incendios","date":"2026-07-10","sheet":"Arquitectura A103 / p. 5; Estructura A201 / p. 4"} | ["Envolvente exterior controlada por la planta de arquitectura; no se han modelado individualmente todas las capas de acabado.","Registro de líneas del PDF general con envolvente de 10,2 × 8,2 m. Estimación de trabajo de implantación de ±0,15 m, pendiente de CAD nativo; no constituye una precisión topográfica garantizada."] | {"horizontalStatus":"derivado","verticalStatus":"derivado","baseElevationM":286.25,"note":"Registro de líneas del PDF general con envolvente de 10,2 × 8,2 m. Estimación de trabajo de implantación de ±0,15 m, pendiente de CAD nativo; no constituye una precisión topográfica garantizada."} | {"Pset_WallCommon":{"IsExternal":{"value":true,"source":"ARQ-SB-20260710 · A101, A103 y alzados; elemento de la envolvente exterior identificada en planta","status":"known"}}} | {"boundingBoxM":{"min":[18.022782,33.330015,1.25],"max":[19.337908,33.705216,2.45]},"extentsM":[1.315126,0.375201,1.2],"meshSurfaceM2":4.119999,"meshVolumeM3":0.312,"closedSolid":true,"basis":"Geometría triangulada releída del IFC; envolventes y magnitudes no contractuales."} | {"material":true,"document":true,"quantities":true,"containerGuid":"0Wh59pm9LO_einrwiq6Es1","containerName":"Planta baja"} | {"id":"architecture","name":"Arquitectura"} | {"profileId":"concrete_precast","name":"Hormigón prefabricado","materialName":"Hormigón prefabricado macizo","physicalMaterialStatus":"known","physicalMaterialSource":"ARQ-SB-20260710 · Arquitectura A103 / p. 5; Estructura A201 / p. 4","appearanceStatus":"criterio_visual","appearanceBasis":"Interpretación visual del material documental; el acabado, tono y parámetros PBR no son una especificación contractual.","note":"La apariencia gráfica no modifica ni confirma la especificación física del material."} | {"elementId":"pump_house_0022","ifcGuid":"3zsDYfSgzJ68TInMVRzvH7","ifcClass":"IfcWall","buildingId":"pump_house","buildingName":"Sala de bombas contra incendios","sourceDocumentId":"ARQ-SB-20260710","sourceRepresentationKind":"documentary_mesh"} | {"layerId":"architecture","layerName":"Arquitectura","role":"Muro","basis":"Clasificación por función del elemento; no modifica las especificaciones documentales."} | architecture | {"profileId":"concrete_precast","name":"Hormigón prefabricado","status":"criterio_visual","basis":"Interpretación visual del material documental; el acabado, tono y parámetros PBR no son una especificación contractual.","physicalMaterialUnchanged":true} | ARQ-SB-20260710 · Arquitectura A103 / p. 5; Estructura A201 / p. 4 | Dimensiones contrastadas con los planos; reconstrucción geométrica a partir de documentación de diseño. | 0.2 | Muros segmentados con huecos reales para puertas y ventanas. | Envolvente exterior controlada por la planta de arquitectura; no se han modelado individualmente todas las capas de acabado. | Registro de líneas del PDF general con envolvente de 10,2 × 8,2 m. Estimación de trabajo de implantación de ±0,15 m, pendiente de CAD nativo; no constituye una precisión topográfica garantizada. | Arquitectura | ARQ-SB-20260710 · Arquitectura A103 / p. 5; Estructura A201 / p. 4 | 286.25 | Arquitectura | Hormigón prefabricado | concrete_precast | [0.756863,0.752941,0.717647] | 0.86 | 0 | Interpretación visual del material documental; el acabado, tono y parámetros PBR no son una especificación contractual. | Arquitectura; BIM · Arquitectura
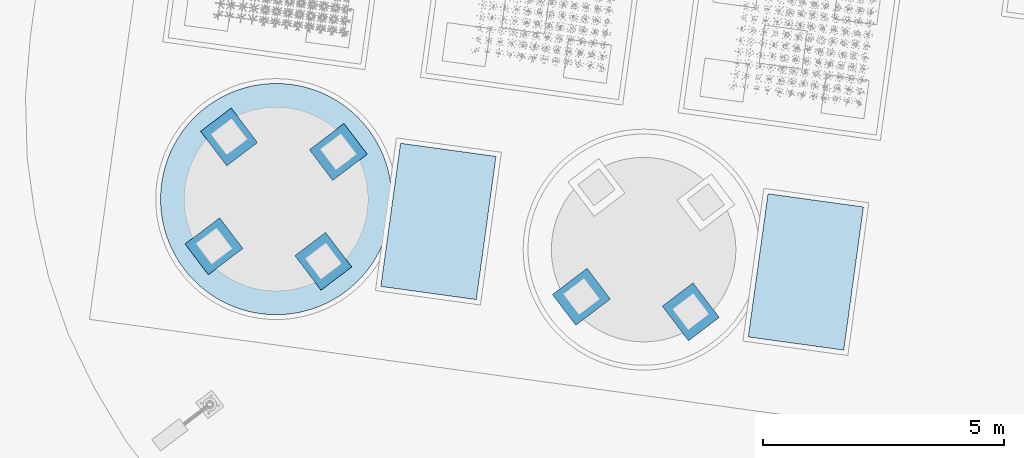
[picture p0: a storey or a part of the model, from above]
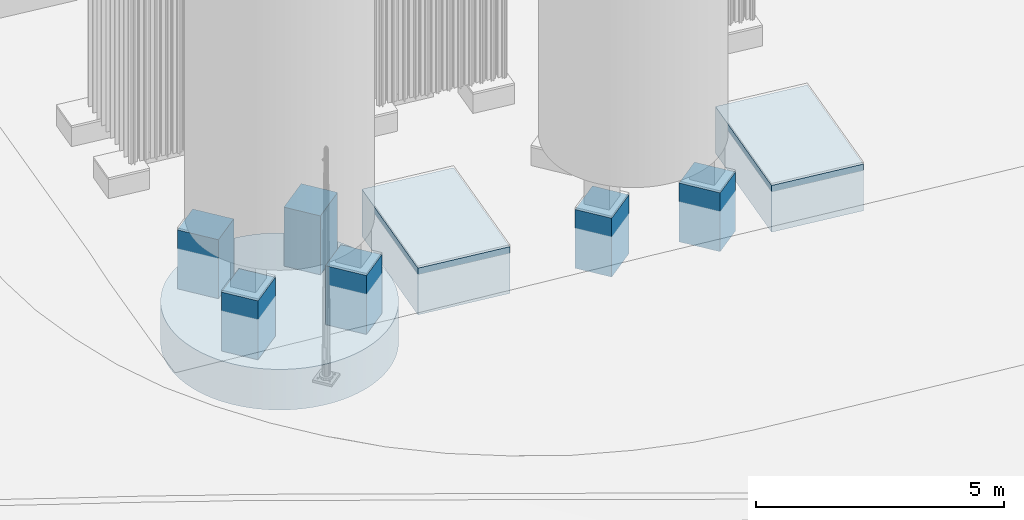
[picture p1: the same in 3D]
Properties of the parts of a building model (IFC4), part 115 of 134

# IfcWall (187)
Name | Document | Material = JH_Trazabilidad, Material = name | Dimensiones de la caja local del elemento (X, Y, Z) | Cota mínima absoluta de la malla (m) | Cota máxima absoluta de la malla (m) | Volumen geométrico bruto (m3) = Volumen geométrico (m³) | Reference = Identificador del elemento = Identificador | IsExternal | ExtensionX (m) | ExtensionY (m) | ExtensionZ (m) | SuperficieDeLaMalla (m2) | VolumenGeometrico (m3) = GrossVolume (m3) | buildingId | buildingName = Edificio | material | dimensions | JH_InformacionBIM, source = DocumentoFuente | issues = IncidenciasPendientes | positioning = PosicionYEstado | commonProperties | geometryMetrics | ifcAssociations | visualLayer | materialAppearance | visualizationIdentity | classification | layerId = IdentificadorCapa | appearance | Planos de referencia | Base geométrica | Espesor del muro (m) = Espesor del muro (m) | Tratamiento de los huecos | Representación de los acabados | Estado de la implantación | Disciplina | Referencia del material = JH_EvidenciaDeMaterial, source | Cota de planta baja terminada (m) | Capa BIM = NombreCapa | Acabado de visualización = Acabado | Perfil | ColorRGB | Rugosidad | Metallicidad | Referencia | Group | Discrepancia entre versiones
Sala de bombas contra incendios · Panel sándwich de fachada con núcleo de lana de roca · eje B · tramo 01 | Planos de arquitectura de la sala de bombas contra incendios; Planos de arquitectura de la sala de bombas contra incendios | Panel sándwich de acero con núcleo de lana de roca | 2.4 × 0.1 × 1.1 | 287.45 | 288.55 | 0.264 | pump_house_0023 | yes | 2.39125 | 0.425957 | 1.1 | 5.98 | 0.264 | pump_house | Sala de bombas contra incendios | {"name":"Panel sándwich de acero con núcleo de lana de roca","source":"ARQ-SB-20260710 · Arquitectura A103 / p. 5; A301Cuadro de materiales ; ARQ-OF-20260710 · A301 / p. 16, bloque correspondiente a la sala de bombas","status":"known"} | {"documented":[{"label":"Espesor del muro","value":0.1,"unit":"m","source":"ARQ-SB-20260710 · Arquitectura A103 / p. 5; A301Cuadro de materiales ","status":"documentado"}],"geometry":[{"label":"Dimensiones de la caja local del elemento (X, Y, Z)","value":"2.4 × 0.1 × 1.1","unit":"m","source":"Malla triangulada del elemento en ejes locales del edificio","status":"derivado"},{"label":"Cota mínima absoluta de la malla","value":287.45,"unit":"m","source":"Malla de proyecto y origen altimétrico 285 m","status":"derivado"},{"label":"Cota máxima absoluta de la malla","value":288.55,"unit":"m","source":"Malla de proyecto y origen altimétrico 285 m","status":"derivado"},{"label":"Volumen geométrico bruto","value":0.264,"unit":"m³","source":"Malla cerrada del elemento","status":"derivado"}],"notes":["Las dimensiones documentadas proceden de anotaciones o cuadros; la caja y el volumen se calculan a partir de la malla.","El volumen es exclusivamente geométrico y bruto; no representa una medición neta de material ni una cantidad de compra."]} | {"documentId":"ARQ-SB-20260710","title":"Planos de arquitectura de la sala de bombas contra incendios","date":"2026-07-10","sheet":"Arquitectura A103 / p. 5; A301Cuadro de materiales "} | ["Envolvente exterior controlada por la planta de arquitectura; no se han modelado individualmente todas las capas de acabado.","Registro de líneas del PDF general con envolvente de 10,2 × 8,2 m. Estimación de trabajo de implantación de ±0,15 m, pendiente de CAD nativo; no constituye una precisión topográfica garantizada."] | {"horizontalStatus":"derivado","verticalStatus":"derivado","baseElevationM":286.25,"note":"Registro de líneas del PDF general con envolvente de 10,2 × 8,2 m. Estimación de trabajo de implantación de ±0,15 m, pendiente de CAD nativo; no constituye una precisión topográfica garantizada."} | {"Pset_WallCommon":{"IsExternal":{"value":true,"source":"ARQ-SB-20260710 · A101, A103 y alzados; elemento de la envolvente exterior identificada en planta","status":"known"}}} | {"boundingBoxM":{"min":[9.219344,34.491474,2.45],"max":[11.610598,34.917431,3.55]},"extentsM":[2.391254,0.425957,1.1],"meshSurfaceM2":5.979998,"meshVolumeM3":0.264,"closedSolid":true,"basis":"Geometría triangulada releída del IFC; envolventes y magnitudes no contractuales."} | {"material":true,"document":true,"quantities":true,"containerGuid":"0Wh59pm9LO_einrwiq6Es1","containerName":"Planta baja"} | {"id":"architecture","name":"Arquitectura"} | {"profileId":"sandwich_panel","name":"Panel sándwich · chapa gris clara","materialName":"Panel sándwich de acero con núcleo de lana de roca","physicalMaterialStatus":"known","physicalMaterialSource":"ARQ-SB-20260710 · Arquitectura A103 / p. 5; A301Cuadro de materiales ; ARQ-OF-20260710 · A301 / p. 16, bloque correspondiente a la sala de bombas","appearanceStatus":"criterio_visual","appearanceBasis":"Interpretación visual del material documental; el acabado, tono y parámetros PBR no son una especificación contractual.","note":"La apariencia gráfica no modifica ni confirma la especificación física del material."} | {"elementId":"pump_house_0023","ifcGuid":"3zZuYwwubG$u$3F5aDZ5g8","ifcClass":"IfcWall","buildingId":"pump_house","buildingName":"Sala de bombas contra incendios","sourceDocumentId":"ARQ-SB-20260710","sourceRepresentationKind":"documentary_mesh"} | {"layerId":"architecture","layerName":"Arquitectura","role":"Muro","basis":"Clasificación por función del elemento; no modifica las especificaciones documentales."} | architecture | {"profileId":"sandwich_panel","name":"Panel sándwich · chapa gris clara","status":"criterio_visual","basis":"Interpretación visual del material documental; el acabado, tono y parámetros PBR no son una especificación contractual.","physicalMaterialUnchanged":true} | ARQ-SB-20260710 · Arquitectura A103 / p. 5; A301Cuadro de materiales | Dimensiones contrastadas con los planos; reconstrucción geométrica a partir de documentación de diseño. | 0.1 | Muros segmentados con huecos reales para puertas y ventanas. | Envolvente exterior controlada por la planta de arquitectura; no se han modelado individualmente todas las capas de acabado. | Registro de líneas del PDF general con envolvente de 10,2 × 8,2 m. Estimación de trabajo de implantación de ±0,15 m, pendiente de CAD nativo; no constituye una precisión topográfica garantizada. | Arquitectura | ARQ-SB-20260710 · Arquitectura A103 / p. 5; A301Cuadro de materiales ; ARQ-OF-20260710 · A301 / p. 16, bloque correspondiente a la sala de bombas | 286.25 | Arquitectura | Panel sándwich · chapa gris clara | sandwich_panel | [0.85098,0.87451,0.87451] | 0.48 | 0.28 | Interpretación visual del material documental; el acabado, tono y parámetros PBR no son una especificación contractual. | Arquitectura; BIM · Arquitectura
Sala de bombas contra incendios · Panel sándwich de fachada con núcleo de lana de roca · eje B · tramo 02 | Planos de arquitectura de la sala de bombas contra incendios; Planos de arquitectura de la sala de bombas contra incendios | Panel sándwich de acero con núcleo de lana de roca | 2.4 × 0.1 × 0.3 | 288.55 | 288.85 | 0.072 | pump_house_0024 | yes | 2.39125 | 0.425957 | 0.3 | 1.98 | 0.0719999 | pump_house | Sala de bombas contra incendios | {"name":"Panel sándwich de acero con núcleo de lana de roca","source":"ARQ-SB-20260710 · Arquitectura A103 / p. 5; A301Cuadro de materiales ; ARQ-OF-20260710 · A301 / p. 16, bloque correspondiente a la sala de bombas","status":"known"} | {"documented":[{"label":"Espesor del muro","value":0.1,"unit":"m","source":"ARQ-SB-20260710 · Arquitectura A103 / p. 5; A301Cuadro de materiales ","status":"documentado"}],"geometry":[{"label":"Dimensiones de la caja local del elemento (X, Y, Z)","value":"2.4 × 0.1 × 0.3","unit":"m","source":"Malla triangulada del elemento en ejes locales del edificio","status":"derivado"},{"label":"Cota mínima absoluta de la malla","value":288.55,"unit":"m","source":"Malla de proyecto y origen altimétrico 285 m","status":"derivado"},{"label":"Cota máxima absoluta de la malla","value":288.85,"unit":"m","source":"Malla de proyecto y origen altimétrico 285 m","status":"derivado"},{"label":"Volumen geométrico bruto","value":0.072,"unit":"m³","source":"Malla cerrada del elemento","status":"derivado"}],"notes":["Las dimensiones documentadas proceden de anotaciones o cuadros; la caja y el volumen se calculan a partir de la malla.","El volumen es exclusivamente geométrico y bruto; no representa una medición neta de material ni una cantidad de compra."]} | {"documentId":"ARQ-SB-20260710","title":"Planos de arquitectura de la sala de bombas contra incendios","date":"2026-07-10","sheet":"Arquitectura A103 / p. 5; A301Cuadro de materiales "} | ["Envolvente exterior controlada por la planta de arquitectura; no se han modelado individualmente todas las capas de acabado.","Registro de líneas del PDF general con envolvente de 10,2 × 8,2 m. Estimación de trabajo de implantación de ±0,15 m, pendiente de CAD nativo; no constituye una precisión topográfica garantizada."] | {"horizontalStatus":"derivado","verticalStatus":"derivado","baseElevationM":286.25,"note":"Registro de líneas del PDF general con envolvente de 10,2 × 8,2 m. Estimación de trabajo de implantación de ±0,15 m, pendiente de CAD nativo; no constituye una precisión topográfica garantizada."} | {"Pset_WallCommon":{"IsExternal":{"value":true,"source":"ARQ-SB-20260710 · A101, A103 y alzados; elemento de la envolvente exterior identificada en planta","status":"known"}}} | {"boundingBoxM":{"min":[9.219344,34.491474,3.55],"max":[11.610598,34.917431,3.85]},"extentsM":[2.391254,0.425957,0.3],"meshSurfaceM2":1.979999,"meshVolumeM3":0.072,"closedSolid":true,"basis":"Geometría triangulada releída del IFC; envolventes y magnitudes no contractuales."} | {"material":true,"document":true,"quantities":true,"containerGuid":"0Wh59pm9LO_einrwiq6Es1","containerName":"Planta baja"} | {"id":"architecture","name":"Arquitectura"} | {"profileId":"sandwich_panel","name":"Panel sándwich · chapa gris clara","materialName":"Panel sándwich de acero con núcleo de lana de roca","physicalMaterialStatus":"known","physicalMaterialSource":"ARQ-SB-20260710 · Arquitectura A103 / p. 5; A301Cuadro de materiales ; ARQ-OF-20260710 · A301 / p. 16, bloque correspondiente a la sala de bombas","appearanceStatus":"criterio_visual","appearanceBasis":"Interpretación visual del material documental; el acabado, tono y parámetros PBR no son una especificación contractual.","note":"La apariencia gráfica no modifica ni confirma la especificación física del material."} | {"elementId":"pump_house_0024","ifcGuid":"174f20u2zVTeV2JUgl5_fG","ifcClass":"IfcWall","buildingId":"pump_house","buildingName":"Sala de bombas contra incendios","sourceDocumentId":"ARQ-SB-20260710","sourceRepresentationKind":"documentary_mesh"} | {"layerId":"architecture","layerName":"Arquitectura","role":"Muro","basis":"Clasificación por función del elemento; no modifica las especificaciones documentales."} | architecture | {"profileId":"sandwich_panel","name":"Panel sándwich · chapa gris clara","status":"criterio_visual","basis":"Interpretación visual del material documental; el acabado, tono y parámetros PBR no son una especificación contractual.","physicalMaterialUnchanged":true} | ARQ-SB-20260710 · Arquitectura A103 / p. 5; A301Cuadro de materiales | Dimensiones contrastadas con los planos; reconstrucción geométrica a partir de documentación de diseño. | 0.1 | Muros segmentados con huecos reales para puertas y ventanas. | Envolvente exterior controlada por la planta de arquitectura; no se han modelado individualmente todas las capas de acabado. | Registro de líneas del PDF general con envolvente de 10,2 × 8,2 m. Estimación de trabajo de implantación de ±0,15 m, pendiente de CAD nativo; no constituye una precisión topográfica garantizada. | Arquitectura | ARQ-SB-20260710 · Arquitectura A103 / p. 5; A301Cuadro de materiales ; ARQ-OF-20260710 · A301 / p. 16, bloque correspondiente a la sala de bombas | 286.25 | Arquitectura | Panel sándwich · chapa gris clara | sandwich_panel | [0.85098,0.87451,0.87451] | 0.48 | 0.28 | Interpretación visual del material documental; el acabado, tono y parámetros PBR no son una especificación contractual. | Arquitectura; BIM · Arquitectura
Sala de bombas contra incendios · Panel sándwich de fachada con núcleo de lana de roca · eje B · tramo 03 | Planos de arquitectura de la sala de bombas contra incendios; Planos de arquitectura de la sala de bombas contra incendios | Panel sándwich de acero con núcleo de lana de roca | 2.4 × 0.1 × 3 | 288.85 | 291.85 | 0.72 | pump_house_0025 | yes | 2.39125 | 0.425957 | 3 | 15.48 | 0.719999 | pump_house | Sala de bombas contra incendios | {"name":"Panel sándwich de acero con núcleo de lana de roca","source":"ARQ-SB-20260710 · Arquitectura A103 / p. 5; A301Cuadro de materiales ; ARQ-OF-20260710 · A301 / p. 16, bloque correspondiente a la sala de bombas","status":"known"} | {"documented":[{"label":"Espesor del muro","value":0.1,"unit":"m","source":"ARQ-SB-20260710 · Arquitectura A103 / p. 5; A301Cuadro de materiales ","status":"documentado"}],"geometry":[{"label":"Dimensiones de la caja local del elemento (X, Y, Z)","value":"2.4 × 0.1 × 3","unit":"m","source":"Malla triangulada del elemento en ejes locales del edificio","status":"derivado"},{"label":"Cota mínima absoluta de la malla","value":288.85,"unit":"m","source":"Malla de proyecto y origen altimétrico 285 m","status":"derivado"},{"label":"Cota máxima absoluta de la malla","value":291.85,"unit":"m","source":"Malla de proyecto y origen altimétrico 285 m","status":"derivado"},{"label":"Volumen geométrico bruto","value":0.72,"unit":"m³","source":"Malla cerrada del elemento","status":"derivado"}],"notes":["Las dimensiones documentadas proceden de anotaciones o cuadros; la caja y el volumen se calculan a partir de la malla.","El volumen es exclusivamente geométrico y bruto; no representa una medición neta de material ni una cantidad de compra."]} | {"documentId":"ARQ-SB-20260710","title":"Planos de arquitectura de la sala de bombas contra incendios","date":"2026-07-10","sheet":"Arquitectura A103 / p. 5; A301Cuadro de materiales "} | ["Envolvente exterior controlada por la planta de arquitectura; no se han modelado individualmente todas las capas de acabado.","Registro de líneas del PDF general con envolvente de 10,2 × 8,2 m. Estimación de trabajo de implantación de ±0,15 m, pendiente de CAD nativo; no constituye una precisión topográfica garantizada."] | {"horizontalStatus":"derivado","verticalStatus":"derivado","baseElevationM":286.25,"note":"Registro de líneas del PDF general con envolvente de 10,2 × 8,2 m. Estimación de trabajo de implantación de ±0,15 m, pendiente de CAD nativo; no constituye una precisión topográfica garantizada."} | {"Pset_WallCommon":{"IsExternal":{"value":true,"source":"ARQ-SB-20260710 · A101, A103 y alzados; elemento de la envolvente exterior identificada en planta","status":"known"}}} | {"boundingBoxM":{"min":[9.219344,34.491474,3.85],"max":[11.610598,34.917431,6.85]},"extentsM":[2.391254,0.425957,3.0],"meshSurfaceM2":15.479996,"meshVolumeM3":0.719999,"closedSolid":true,"basis":"Geometría triangulada releída del IFC; envolventes y magnitudes no contractuales."} | {"material":true,"document":true,"quantities":true,"containerGuid":"0Wh59pm9LO_einrwiq6Es1","containerName":"Planta baja"} | {"id":"architecture","name":"Arquitectura"} | {"profileId":"sandwich_panel","name":"Panel sándwich · chapa gris clara","materialName":"Panel sándwich de acero con núcleo de lana de roca","physicalMaterialStatus":"known","physicalMaterialSource":"ARQ-SB-20260710 · Arquitectura A103 / p. 5; A301Cuadro de materiales ; ARQ-OF-20260710 · A301 / p. 16, bloque correspondiente a la sala de bombas","appearanceStatus":"criterio_visual","appearanceBasis":"Interpretación visual del material documental; el acabado, tono y parámetros PBR no son una especificación contractual.","note":"La apariencia gráfica no modifica ni confirma la especificación física del material."} | {"elementId":"pump_house_0025","ifcGuid":"3so8YeoV5UDOqrFLCSYhQA","ifcClass":"IfcWall","buildingId":"pump_house","buildingName":"Sala de bombas contra incendios","sourceDocumentId":"ARQ-SB-20260710","sourceRepresentationKind":"documentary_mesh"} | {"layerId":"architecture","layerName":"Arquitectura","role":"Muro","basis":"Clasificación por función del elemento; no modifica las especificaciones documentales."} | architecture | {"profileId":"sandwich_panel","name":"Panel sándwich · chapa gris clara","status":"criterio_visual","basis":"Interpretación visual del material documental; el acabado, tono y parámetros PBR no son una especificación contractual.","physicalMaterialUnchanged":true} | ARQ-SB-20260710 · Arquitectura A103 / p. 5; A301Cuadro de materiales | Dimensiones contrastadas con los planos; reconstrucción geométrica a partir de documentación de diseño. | 0.1 | Muros segmentados con huecos reales para puertas y ventanas. | Envolvente exterior controlada por la planta de arquitectura; no se han modelado individualmente todas las capas de acabado. | Registro de líneas del PDF general con envolvente de 10,2 × 8,2 m. Estimación de trabajo de implantación de ±0,15 m, pendiente de CAD nativo; no constituye una precisión topográfica garantizada. | Arquitectura | ARQ-SB-20260710 · Arquitectura A103 / p. 5; A301Cuadro de materiales ; ARQ-OF-20260710 · A301 / p. 16, bloque correspondiente a la sala de bombas | 286.25 | Arquitectura | Panel sándwich · chapa gris clara | sandwich_panel | [0.85098,0.87451,0.87451] | 0.48 | 0.28 | Interpretación visual del material documental; el acabado, tono y parámetros PBR no son una especificación contractual. | Arquitectura; BIM · Arquitectura
Sala de bombas contra incendios · Panel sándwich de fachada con núcleo de lana de roca · eje B · tramo 04 | Planos de arquitectura de la sala de bombas contra incendios; Planos de arquitectura de la sala de bombas contra incendios | Panel sándwich de acero con núcleo de lana de roca | 4 × 0.1 × 3 | 288.85 | 291.85 | 1.2 | pump_house_0026 | yes | 3.97634 | 0.643884 | 3 | 25.4 | 1.2 | pump_house | Sala de bombas contra incendios | {"name":"Panel sándwich de acero con núcleo de lana de roca","source":"ARQ-SB-20260710 · Arquitectura A103 / p. 5; A301Cuadro de materiales ; ARQ-OF-20260710 · A301 / p. 16, bloque correspondiente a la sala de bombas","status":"known"} | {"documented":[{"label":"Espesor del muro","value":0.1,"unit":"m","source":"ARQ-SB-20260710 · Arquitectura A103 / p. 5; A301Cuadro de materiales ","status":"documentado"}],"geometry":[{"label":"Dimensiones de la caja local del elemento (X, Y, Z)","value":"4 × 0.1 × 3","unit":"m","source":"Malla triangulada del elemento en ejes locales del edificio","status":"derivado"},{"label":"Cota mínima absoluta de la malla","value":288.85,"unit":"m","source":"Malla de proyecto y origen altimétrico 285 m","status":"derivado"},{"label":"Cota máxima absoluta de la malla","value":291.85,"unit":"m","source":"Malla de proyecto y origen altimétrico 285 m","status":"derivado"},{"label":"Volumen geométrico bruto","value":1.2,"unit":"m³","source":"Malla cerrada del elemento","status":"derivado"}],"notes":["Las dimensiones documentadas proceden de anotaciones o cuadros; la caja y el volumen se calculan a partir de la malla.","El volumen es exclusivamente geométrico y bruto; no representa una medición neta de material ni una cantidad de compra."]} | {"documentId":"ARQ-SB-20260710","title":"Planos de arquitectura de la sala de bombas contra incendios","date":"2026-07-10","sheet":"Arquitectura A103 / p. 5; A301Cuadro de materiales "} | ["Envolvente exterior controlada por la planta de arquitectura; no se han modelado individualmente todas las capas de acabado.","Registro de líneas del PDF general con envolvente de 10,2 × 8,2 m. Estimación de trabajo de implantación de ±0,15 m, pendiente de CAD nativo; no constituye una precisión topográfica garantizada."] | {"horizontalStatus":"derivado","verticalStatus":"derivado","baseElevationM":286.25,"note":"Registro de líneas del PDF general con envolvente de 10,2 × 8,2 m. Estimación de trabajo de implantación de ±0,15 m, pendiente de CAD nativo; no constituye una precisión topográfica garantizada."} | {"Pset_WallCommon":{"IsExternal":{"value":true,"source":"ARQ-SB-20260710 · A101, A103 y alzados; elemento de la envolvente exterior identificada en planta","status":"known"}}} | {"boundingBoxM":{"min":[11.596977,33.946658,3.85],"max":[15.573321,34.590542,6.85]},"extentsM":[3.976344,0.643884,3.0],"meshSurfaceM2":25.400001,"meshVolumeM3":1.199999,"closedSolid":true,"basis":"Geometría triangulada releída del IFC; envolventes y magnitudes no contractuales."} | {"material":true,"document":true,"quantities":true,"containerGuid":"0Wh59pm9LO_einrwiq6Es1","containerName":"Planta baja"} | {"id":"architecture","name":"Arquitectura"} | {"profileId":"sandwich_panel","name":"Panel sándwich · chapa gris clara","materialName":"Panel sándwich de acero con núcleo de lana de roca","physicalMaterialStatus":"known","physicalMaterialSource":"ARQ-SB-20260710 · Arquitectura A103 / p. 5; A301Cuadro de materiales ; ARQ-OF-20260710 · A301 / p. 16, bloque correspondiente a la sala de bombas","appearanceStatus":"criterio_visual","appearanceBasis":"Interpretación visual del material documental; el acabado, tono y parámetros PBR no son una especificación contractual.","note":"La apariencia gráfica no modifica ni confirma la especificación física del material."} | {"elementId":"pump_house_0026","ifcGuid":"1IfykPs59MNx$QD1lKsczO","ifcClass":"IfcWall","buildingId":"pump_house","buildingName":"Sala de bombas contra incendios","sourceDocumentId":"ARQ-SB-20260710","sourceRepresentationKind":"documentary_mesh"} | {"layerId":"architecture","layerName":"Arquitectura","role":"Muro","basis":"Clasificación por función del elemento; no modifica las especificaciones documentales."} | architecture | {"profileId":"sandwich_panel","name":"Panel sándwich · chapa gris clara","status":"criterio_visual","basis":"Interpretación visual del material documental; el acabado, tono y parámetros PBR no son una especificación contractual.","physicalMaterialUnchanged":true} | ARQ-SB-20260710 · Arquitectura A103 / p. 5; A301Cuadro de materiales | Dimensiones contrastadas con los planos; reconstrucción geométrica a partir de documentación de diseño. | 0.1 | Muros segmentados con huecos reales para puertas y ventanas. | Envolvente exterior controlada por la planta de arquitectura; no se han modelado individualmente todas las capas de acabado. | Registro de líneas del PDF general con envolvente de 10,2 × 8,2 m. Estimación de trabajo de implantación de ±0,15 m, pendiente de CAD nativo; no constituye una precisión topográfica garantizada. | Arquitectura | ARQ-SB-20260710 · Arquitectura A103 / p. 5; A301Cuadro de materiales ; ARQ-OF-20260710 · A301 / p. 16, bloque correspondiente a la sala de bombas | 286.25 | Arquitectura | Panel sándwich · chapa gris clara | sandwich_panel | [0.85098,0.87451,0.87451] | 0.48 | 0.28 | Interpretación visual del material documental; el acabado, tono y parámetros PBR no son una especificación contractual. | Arquitectura; BIM · Arquitectura
Sala de bombas contra incendios · Panel sándwich de fachada con núcleo de lana de roca · eje B · tramo 05 | Planos de arquitectura de la sala de bombas contra incendios; Planos de arquitectura de la sala de bombas contra incendios | Panel sándwich de acero con núcleo de lana de roca | 1 × 0.1 × 1.1 | 287.45 | 288.55 | 0.11 | pump_house_0027 | yes | 1.0043 | 0.235272 | 1.1 | 2.62 | 0.11 | pump_house | Sala de bombas contra incendios | {"name":"Panel sándwich de acero con núcleo de lana de roca","source":"ARQ-SB-20260710 · Arquitectura A103 / p. 5; A301Cuadro de materiales ; ARQ-OF-20260710 · A301 / p. 16, bloque correspondiente a la sala de bombas","status":"known"} | {"documented":[{"label":"Espesor del muro","value":0.1,"unit":"m","source":"ARQ-SB-20260710 · Arquitectura A103 / p. 5; A301Cuadro de materiales ","status":"documentado"}],"geometry":[{"label":"Dimensiones de la caja local del elemento (X, Y, Z)","value":"1 × 0.1 × 1.1","unit":"m","source":"Malla triangulada del elemento en ejes locales del edificio","status":"derivado"},{"label":"Cota mínima absoluta de la malla","value":287.45,"unit":"m","source":"Malla de proyecto y origen altimétrico 285 m","status":"derivado"},{"label":"Cota máxima absoluta de la malla","value":288.55,"unit":"m","source":"Malla de proyecto y origen altimétrico 285 m","status":"derivado"},{"label":"Volumen geométrico bruto","value":0.11,"unit":"m³","source":"Malla cerrada del elemento","status":"derivado"}],"notes":["Las dimensiones documentadas proceden de anotaciones o cuadros; la caja y el volumen se calculan a partir de la malla.","El volumen es exclusivamente geométrico y bruto; no representa una medición neta de material ni una cantidad de compra."]} | {"documentId":"ARQ-SB-20260710","title":"Planos de arquitectura de la sala de bombas contra incendios","date":"2026-07-10","sheet":"Arquitectura A103 / p. 5; A301Cuadro de materiales "} | ["Envolvente exterior controlada por la planta de arquitectura; no se han modelado individualmente todas las capas de acabado.","Registro de líneas del PDF general con envolvente de 10,2 × 8,2 m. Estimación de trabajo de implantación de ±0,15 m, pendiente de CAD nativo; no constituye una precisión topográfica garantizada."] | {"horizontalStatus":"derivado","verticalStatus":"derivado","baseElevationM":286.25,"note":"Registro de líneas del PDF general con envolvente de 10,2 × 8,2 m. Estimación de trabajo de implantación de ±0,15 m, pendiente de CAD nativo; no constituye una precisión topográfica garantizada."} | {"Pset_WallCommon":{"IsExternal":{"value":true,"source":"ARQ-SB-20260710 · A101, A103 y alzados; elemento de la envolvente exterior identificada en planta","status":"known"}}} | {"boundingBoxM":{"min":[15.559701,33.810454,2.45],"max":[16.564002,34.045726,3.55]},"extentsM":[1.004301,0.235272,1.1],"meshSurfaceM2":2.62,"meshVolumeM3":0.11,"closedSolid":true,"basis":"Geometría triangulada releída del IFC; envolventes y magnitudes no contractuales."} | {"material":true,"document":true,"quantities":true,"containerGuid":"0Wh59pm9LO_einrwiq6Es1","containerName":"Planta baja"} | {"id":"architecture","name":"Arquitectura"} | {"profileId":"sandwich_panel","name":"Panel sándwich · chapa gris clara","materialName":"Panel sándwich de acero con núcleo de lana de roca","physicalMaterialStatus":"known","physicalMaterialSource":"ARQ-SB-20260710 · Arquitectura A103 / p. 5; A301Cuadro de materiales ; ARQ-OF-20260710 · A301 / p. 16, bloque correspondiente a la sala de bombas","appearanceStatus":"criterio_visual","appearanceBasis":"Interpretación visual del material documental; el acabado, tono y parámetros PBR no son una especificación contractual.","note":"La apariencia gráfica no modifica ni confirma la especificación física del material."} | {"elementId":"pump_house_0027","ifcGuid":"2BbBXCuSLM0eM$VrD6VMrB","ifcClass":"IfcWall","buildingId":"pump_house","buildingName":"Sala de bombas contra incendios","sourceDocumentId":"ARQ-SB-20260710","sourceRepresentationKind":"documentary_mesh"} | {"layerId":"architecture","layerName":"Arquitectura","role":"Muro","basis":"Clasificación por función del elemento; no modifica las especificaciones documentales."} | architecture | {"profileId":"sandwich_panel","name":"Panel sándwich · chapa gris clara","status":"criterio_visual","basis":"Interpretación visual del material documental; el acabado, tono y parámetros PBR no son una especificación contractual.","physicalMaterialUnchanged":true} | ARQ-SB-20260710 · Arquitectura A103 / p. 5; A301Cuadro de materiales | Dimensiones contrastadas con los planos; reconstrucción geométrica a partir de documentación de diseño. | 0.1 | Muros segmentados con huecos reales para puertas y ventanas. | Envolvente exterior controlada por la planta de arquitectura; no se han modelado individualmente todas las capas de acabado. | Registro de líneas del PDF general con envolvente de 10,2 × 8,2 m. Estimación de trabajo de implantación de ±0,15 m, pendiente de CAD nativo; no constituye una precisión topográfica garantizada. | Arquitectura | ARQ-SB-20260710 · Arquitectura A103 / p. 5; A301Cuadro de materiales ; ARQ-OF-20260710 · A301 / p. 16, bloque correspondiente a la sala de bombas | 286.25 | Arquitectura | Panel sándwich · chapa gris clara | sandwich_panel | [0.85098,0.87451,0.87451] | 0.48 | 0.28 | Interpretación visual del material documental; el acabado, tono y parámetros PBR no son una especificación contractual. | Arquitectura; BIM · Arquitectura
Sala de bombas contra incendios · Panel sándwich de fachada con núcleo de lana de roca · eje B · tramo 06 | Planos de arquitectura de la sala de bombas contra incendios; Planos de arquitectura de la sala de bombas contra incendios | Panel sándwich de acero con núcleo de lana de roca | 1 × 0.1 × 0.3 | 288.55 | 288.85 | 0.03 | pump_house_0028 | yes | 1.0043 | 0.235272 | 0.3 | 0.86 | 0.03 | pump_house | Sala de bombas contra incendios | {"name":"Panel sándwich de acero con núcleo de lana de roca","source":"ARQ-SB-20260710 · Arquitectura A103 / p. 5; A301Cuadro de materiales ; ARQ-OF-20260710 · A301 / p. 16, bloque correspondiente a la sala de bombas","status":"known"} | {"documented":[{"label":"Espesor del muro","value":0.1,"unit":"m","source":"ARQ-SB-20260710 · Arquitectura A103 / p. 5; A301Cuadro de materiales ","status":"documentado"}],"geometry":[{"label":"Dimensiones de la caja local del elemento (X, Y, Z)","value":"1 × 0.1 × 0.3","unit":"m","source":"Malla triangulada del elemento en ejes locales del edificio","status":"derivado"},{"label":"Cota mínima absoluta de la malla","value":288.55,"unit":"m","source":"Malla de proyecto y origen altimétrico 285 m","status":"derivado"},{"label":"Cota máxima absoluta de la malla","value":288.85,"unit":"m","source":"Malla de proyecto y origen altimétrico 285 m","status":"derivado"},{"label":"Volumen geométrico bruto","value":0.03,"unit":"m³","source":"Malla cerrada del elemento","status":"derivado"}],"notes":["Las dimensiones documentadas proceden de anotaciones o cuadros; la caja y el volumen se calculan a partir de la malla.","El volumen es exclusivamente geométrico y bruto; no representa una medición neta de material ni una cantidad de compra."]} | {"documentId":"ARQ-SB-20260710","title":"Planos de arquitectura de la sala de bombas contra incendios","date":"2026-07-10","sheet":"Arquitectura A103 / p. 5; A301Cuadro de materiales "} | ["Envolvente exterior controlada por la planta de arquitectura; no se han modelado individualmente todas las capas de acabado.","Registro de líneas del PDF general con envolvente de 10,2 × 8,2 m. Estimación de trabajo de implantación de ±0,15 m, pendiente de CAD nativo; no constituye una precisión topográfica garantizada."] | {"horizontalStatus":"derivado","verticalStatus":"derivado","baseElevationM":286.25,"note":"Registro de líneas del PDF general con envolvente de 10,2 × 8,2 m. Estimación de trabajo de implantación de ±0,15 m, pendiente de CAD nativo; no constituye una precisión topográfica garantizada."} | {"Pset_WallCommon":{"IsExternal":{"value":true,"source":"ARQ-SB-20260710 · A101, A103 y alzados; elemento de la envolvente exterior identificada en planta","status":"known"}}} | {"boundingBoxM":{"min":[15.559701,33.810454,3.55],"max":[16.564002,34.045726,3.85]},"extentsM":[1.004301,0.235272,0.3],"meshSurfaceM2":0.86,"meshVolumeM3":0.03,"closedSolid":true,"basis":"Geometría triangulada releída del IFC; envolventes y magnitudes no contractuales."} | {"material":true,"document":true,"quantities":true,"containerGuid":"0Wh59pm9LO_einrwiq6Es1","containerName":"Planta baja"} | {"id":"architecture","name":"Arquitectura"} | {"profileId":"sandwich_panel","name":"Panel sándwich · chapa gris clara","materialName":"Panel sándwich de acero con núcleo de lana de roca","physicalMaterialStatus":"known","physicalMaterialSource":"ARQ-SB-20260710 · Arquitectura A103 / p. 5; A301Cuadro de materiales ; ARQ-OF-20260710 · A301 / p. 16, bloque correspondiente a la sala de bombas","appearanceStatus":"criterio_visual","appearanceBasis":"Interpretación visual del material documental; el acabado, tono y parámetros PBR no son una especificación contractual.","note":"La apariencia gráfica no modifica ni confirma la especificación física del material."} | {"elementId":"pump_house_0028","ifcGuid":"1aernhenjHOxbFfBRu0g6w","ifcClass":"IfcWall","buildingId":"pump_house","buildingName":"Sala de bombas contra incendios","sourceDocumentId":"ARQ-SB-20260710","sourceRepresentationKind":"documentary_mesh"} | {"layerId":"architecture","layerName":"Arquitectura","role":"Muro","basis":"Clasificación por función del elemento; no modifica las especificaciones documentales."} | architecture | {"profileId":"sandwich_panel","name":"Panel sándwich · chapa gris clara","status":"criterio_visual","basis":"Interpretación visual del material documental; el acabado, tono y parámetros PBR no son una especificación contractual.","physicalMaterialUnchanged":true} | ARQ-SB-20260710 · Arquitectura A103 / p. 5; A301Cuadro de materiales | Dimensiones contrastadas con los planos; reconstrucción geométrica a partir de documentación de diseño. | 0.1 | Muros segmentados con huecos reales para puertas y ventanas. | Envolvente exterior controlada por la planta de arquitectura; no se han modelado individualmente todas las capas de acabado. | Registro de líneas del PDF general con envolvente de 10,2 × 8,2 m. Estimación de trabajo de implantación de ±0,15 m, pendiente de CAD nativo; no constituye una precisión topográfica garantizada. | Arquitectura | ARQ-SB-20260710 · Arquitectura A103 / p. 5; A301Cuadro de materiales ; ARQ-OF-20260710 · A301 / p. 16, bloque correspondiente a la sala de bombas | 286.25 | Arquitectura | Panel sándwich · chapa gris clara | sandwich_panel | [0.85098,0.87451,0.87451] | 0.48 | 0.28 | Interpretación visual del material documental; el acabado, tono y parámetros PBR no son una especificación contractual. | Arquitectura; BIM · Arquitectura
Sala de bombas contra incendios · Panel sándwich de fachada con núcleo de lana de roca · eje B · tramo 07 | Planos de arquitectura de la sala de bombas contra incendios; Planos de arquitectura de la sala de bombas contra incendios | Panel sándwich de acero con núcleo de lana de roca | 1 × 0.1 × 3 | 288.85 | 291.85 | 0.3 | pump_house_0029 | yes | 1.0043 | 0.235272 | 3 | 6.8 | 0.3 | pump_house | Sala de bombas contra incendios | {"name":"Panel sándwich de acero con núcleo de lana de roca","source":"ARQ-SB-20260710 · Arquitectura A103 / p. 5; A301Cuadro de materiales ; ARQ-OF-20260710 · A301 / p. 16, bloque correspondiente a la sala de bombas","status":"known"} | {"documented":[{"label":"Espesor del muro","value":0.1,"unit":"m","source":"ARQ-SB-20260710 · Arquitectura A103 / p. 5; A301Cuadro de materiales ","status":"documentado"}],"geometry":[{"label":"Dimensiones de la caja local del elemento (X, Y, Z)","value":"1 × 0.1 × 3","unit":"m","source":"Malla triangulada del elemento en ejes locales del edificio","status":"derivado"},{"label":"Cota mínima absoluta de la malla","value":288.85,"unit":"m","source":"Malla de proyecto y origen altimétrico 285 m","status":"derivado"},{"label":"Cota máxima absoluta de la malla","value":291.85,"unit":"m","source":"Malla de proyecto y origen altimétrico 285 m","status":"derivado"},{"label":"Volumen geométrico bruto","value":0.3,"unit":"m³","source":"Malla cerrada del elemento","status":"derivado"}],"notes":["Las dimensiones documentadas proceden de anotaciones o cuadros; la caja y el volumen se calculan a partir de la malla.","El volumen es exclusivamente geométrico y bruto; no representa una medición neta de material ni una cantidad de compra."]} | {"documentId":"ARQ-SB-20260710","title":"Planos de arquitectura de la sala de bombas contra incendios","date":"2026-07-10","sheet":"Arquitectura A103 / p. 5; A301Cuadro de materiales "} | ["Envolvente exterior controlada por la planta de arquitectura; no se han modelado individualmente todas las capas de acabado.","Registro de líneas del PDF general con envolvente de 10,2 × 8,2 m. Estimación de trabajo de implantación de ±0,15 m, pendiente de CAD nativo; no constituye una precisión topográfica garantizada."] | {"horizontalStatus":"derivado","verticalStatus":"derivado","baseElevationM":286.25,"note":"Registro de líneas del PDF general con envolvente de 10,2 × 8,2 m. Estimación de trabajo de implantación de ±0,15 m, pendiente de CAD nativo; no constituye una precisión topográfica garantizada."} | {"Pset_WallCommon":{"IsExternal":{"value":true,"source":"ARQ-SB-20260710 · A101, A103 y alzados; elemento de la envolvente exterior identificada en planta","status":"known"}}} | {"boundingBoxM":{"min":[15.559701,33.810454,3.85],"max":[16.564002,34.045726,6.85]},"extentsM":[1.004301,0.235272,3.0],"meshSurfaceM2":6.8,"meshVolumeM3":0.3,"closedSolid":true,"basis":"Geometría triangulada releída del IFC; envolventes y magnitudes no contractuales."} | {"material":true,"document":true,"quantities":true,"containerGuid":"0Wh59pm9LO_einrwiq6Es1","containerName":"Planta baja"} | {"id":"architecture","name":"Arquitectura"} | {"profileId":"sandwich_panel","name":"Panel sándwich · chapa gris clara","materialName":"Panel sándwich de acero con núcleo de lana de roca","physicalMaterialStatus":"known","physicalMaterialSource":"ARQ-SB-20260710 · Arquitectura A103 / p. 5; A301Cuadro de materiales ; ARQ-OF-20260710 · A301 / p. 16, bloque correspondiente a la sala de bombas","appearanceStatus":"criterio_visual","appearanceBasis":"Interpretación visual del material documental; el acabado, tono y parámetros PBR no son una especificación contractual.","note":"La apariencia gráfica no modifica ni confirma la especificación física del material."} | {"elementId":"pump_house_0029","ifcGuid":"1qoTgG0RbNguLlWLVK913L","ifcClass":"IfcWall","buildingId":"pump_house","buildingName":"Sala de bombas contra incendios","sourceDocumentId":"ARQ-SB-20260710","sourceRepresentationKind":"documentary_mesh"} | {"layerId":"architecture","layerName":"Arquitectura","role":"Muro","basis":"Clasificación por función del elemento; no modifica las especificaciones documentales."} | architecture | {"profileId":"sandwich_panel","name":"Panel sándwich · chapa gris clara","status":"criterio_visual","basis":"Interpretación visual del material documental; el acabado, tono y parámetros PBR no son una especificación contractual.","physicalMaterialUnchanged":true} | ARQ-SB-20260710 · Arquitectura A103 / p. 5; A301Cuadro de materiales | Dimensiones contrastadas con los planos; reconstrucción geométrica a partir de documentación de diseño. | 0.1 | Muros segmentados con huecos reales para puertas y ventanas. | Envolvente exterior controlada por la planta de arquitectura; no se han modelado individualmente todas las capas de acabado. | Registro de líneas del PDF general con envolvente de 10,2 × 8,2 m. Estimación de trabajo de implantación de ±0,15 m, pendiente de CAD nativo; no constituye una precisión topográfica garantizada. | Arquitectura | ARQ-SB-20260710 · Arquitectura A103 / p. 5; A301Cuadro de materiales ; ARQ-OF-20260710 · A301 / p. 16, bloque correspondiente a la sala de bombas | 286.25 | Arquitectura | Panel sándwich · chapa gris clara | sandwich_panel | [0.85098,0.87451,0.87451] | 0.48 | 0.28 | Interpretación visual del material documental; el acabado, tono y parámetros PBR no son una especificación contractual. | Arquitectura; BIM · Arquitectura
Sala de bombas contra incendios · Panel sándwich de fachada con núcleo de lana de roca · eje B · tramo 08 | Planos de arquitectura de la sala de bombas contra incendios; Planos de arquitectura de la sala de bombas contra incendios | Panel sándwich de acero con núcleo de lana de roca | 1.5 × 0.1 × 0.3 | 288.55 | 288.85 | 0.045 | pump_house_0030 | yes | 1.49964 | 0.303374 | 0.3 | 1.26 | 0.0449999 | pump_house | Sala de bombas contra incendios | {"name":"Panel sándwich de acero con núcleo de lana de roca","source":"ARQ-SB-20260710 · Arquitectura A103 / p. 5; A301Cuadro de materiales ; ARQ-OF-20260710 · A301 / p. 16, bloque correspondiente a la sala de bombas","status":"known"} | {"documented":[{"label":"Espesor del muro","value":0.1,"unit":"m","source":"ARQ-SB-20260710 · Arquitectura A103 / p. 5; A301Cuadro de materiales ","status":"documentado"}],"geometry":[{"label":"Dimensiones de la caja local del elemento (X, Y, Z)","value":"1.5 × 0.1 × 0.3","unit":"m","source":"Malla triangulada del elemento en ejes locales del edificio","status":"derivado"},{"label":"Cota mínima absoluta de la malla","value":288.55,"unit":"m","source":"Malla de proyecto y origen altimétrico 285 m","status":"derivado"},{"label":"Cota máxima absoluta de la malla","value":288.85,"unit":"m","source":"Malla de proyecto y origen altimétrico 285 m","status":"derivado"},{"label":"Volumen geométrico bruto","value":0.045,"unit":"m³","source":"Malla cerrada del elemento","status":"derivado"}],"notes":["Las dimensiones documentadas proceden de anotaciones o cuadros; la caja y el volumen se calculan a partir de la malla.","El volumen es exclusivamente geométrico y bruto; no representa una medición neta de material ni una cantidad de compra."]} | {"documentId":"ARQ-SB-20260710","title":"Planos de arquitectura de la sala de bombas contra incendios","date":"2026-07-10","sheet":"Arquitectura A103 / p. 5; A301Cuadro de materiales "} | ["Envolvente exterior controlada por la planta de arquitectura; no se han modelado individualmente todas las capas de acabado.","Registro de líneas del PDF general con envolvente de 10,2 × 8,2 m. Estimación de trabajo de implantación de ±0,15 m, pendiente de CAD nativo; no constituye una precisión topográfica garantizada."] | {"horizontalStatus":"derivado","verticalStatus":"derivado","baseElevationM":286.25,"note":"Registro de líneas del PDF general con envolvente de 10,2 × 8,2 m. Estimación de trabajo de implantación de ±0,15 m, pendiente de CAD nativo; no constituye una precisión topográfica garantizada."} | {"Pset_WallCommon":{"IsExternal":{"value":true,"source":"ARQ-SB-20260710 · A101, A103 y alzados; elemento de la envolvente exterior identificada en planta","status":"known"}}} | {"boundingBoxM":{"min":[16.550382,33.606148,3.55],"max":[18.050023,33.909522,3.85]},"extentsM":[1.499641,0.303374,0.3],"meshSurfaceM2":1.259999,"meshVolumeM3":0.045,"closedSolid":true,"basis":"Geometría triangulada releída del IFC; envolventes y magnitudes no contractuales."} | {"material":true,"document":true,"quantities":true,"containerGuid":"0Wh59pm9LO_einrwiq6Es1","containerName":"Planta baja"} | {"id":"architecture","name":"Arquitectura"} | {"profileId":"sandwich_panel","name":"Panel sándwich · chapa gris clara","materialName":"Panel sándwich de acero con núcleo de lana de roca","physicalMaterialStatus":"known","physicalMaterialSource":"ARQ-SB-20260710 · Arquitectura A103 / p. 5; A301Cuadro de materiales ; ARQ-OF-20260710 · A301 / p. 16, bloque correspondiente a la sala de bombas","appearanceStatus":"criterio_visual","appearanceBasis":"Interpretación visual del material documental; el acabado, tono y parámetros PBR no son una especificación contractual.","note":"La apariencia gráfica no modifica ni confirma la especificación física del material."} | {"elementId":"pump_house_0030","ifcGuid":"3RX0wA$lPSGP9EhnCICjJq","ifcClass":"IfcWall","buildingId":"pump_house","buildingName":"Sala de bombas contra incendios","sourceDocumentId":"ARQ-SB-20260710","sourceRepresentationKind":"documentary_mesh"} | {"layerId":"architecture","layerName":"Arquitectura","role":"Muro","basis":"Clasificación por función del elemento; no modifica las especificaciones documentales."} | architecture | {"profileId":"sandwich_panel","name":"Panel sándwich · chapa gris clara","status":"criterio_visual","basis":"Interpretación visual del material documental; el acabado, tono y parámetros PBR no son una especificación contractual.","physicalMaterialUnchanged":true} | ARQ-SB-20260710 · Arquitectura A103 / p. 5; A301Cuadro de materiales | Dimensiones contrastadas con los planos; reconstrucción geométrica a partir de documentación de diseño. | 0.1 | Muros segmentados con huecos reales para puertas y ventanas. | Envolvente exterior controlada por la planta de arquitectura; no se han modelado individualmente todas las capas de acabado. | Registro de líneas del PDF general con envolvente de 10,2 × 8,2 m. Estimación de trabajo de implantación de ±0,15 m, pendiente de CAD nativo; no constituye una precisión topográfica garantizada. | Arquitectura | ARQ-SB-20260710 · Arquitectura A103 / p. 5; A301Cuadro de materiales ; ARQ-OF-20260710 · A301 / p. 16, bloque correspondiente a la sala de bombas | 286.25 | Arquitectura | Panel sándwich · chapa gris clara | sandwich_panel | [0.85098,0.87451,0.87451] | 0.48 | 0.28 | Interpretación visual del material documental; el acabado, tono y parámetros PBR no son una especificación contractual. | Arquitectura; BIM · Arquitectura
Sala de bombas contra incendios · Panel sándwich de fachada con núcleo de lana de roca · eje B · tramo 09 | Planos de arquitectura de la sala de bombas contra incendios; Planos de arquitectura de la sala de bombas contra incendios | Panel sándwich de acero con núcleo de lana de roca | 1.5 × 0.1 × 3 | 288.85 | 291.85 | 0.45 | pump_house_0031 | yes | 1.49964 | 0.303374 | 3 | 9.9 | 0.449999 | pump_house | Sala de bombas contra incendios | {"name":"Panel sándwich de acero con núcleo de lana de roca","source":"ARQ-SB-20260710 · Arquitectura A103 / p. 5; A301Cuadro de materiales ; ARQ-OF-20260710 · A301 / p. 16, bloque correspondiente a la sala de bombas","status":"known"} | {"documented":[{"label":"Espesor del muro","value":0.1,"unit":"m","source":"ARQ-SB-20260710 · Arquitectura A103 / p. 5; A301Cuadro de materiales ","status":"documentado"}],"geometry":[{"label":"Dimensiones de la caja local del elemento (X, Y, Z)","value":"1.5 × 0.1 × 3","unit":"m","source":"Malla triangulada del elemento en ejes locales del edificio","status":"derivado"},{"label":"Cota mínima absoluta de la malla","value":288.85,"unit":"m","source":"Malla de proyecto y origen altimétrico 285 m","status":"derivado"},{"label":"Cota máxima absoluta de la malla","value":291.85,"unit":"m","source":"Malla de proyecto y origen altimétrico 285 m","status":"derivado"},{"label":"Volumen geométrico bruto","value":0.45,"unit":"m³","source":"Malla cerrada del elemento","status":"derivado"}],"notes":["Las dimensiones documentadas proceden de anotaciones o cuadros; la caja y el volumen se calculan a partir de la malla.","El volumen es exclusivamente geométrico y bruto; no representa una medición neta de material ni una cantidad de compra."]} | {"documentId":"ARQ-SB-20260710","title":"Planos de arquitectura de la sala de bombas contra incendios","date":"2026-07-10","sheet":"Arquitectura A103 / p. 5; A301Cuadro de materiales "} | ["Envolvente exterior controlada por la planta de arquitectura; no se han modelado individualmente todas las capas de acabado.","Registro de líneas del PDF general con envolvente de 10,2 × 8,2 m. Estimación de trabajo de implantación de ±0,15 m, pendiente de CAD nativo; no constituye una precisión topográfica garantizada."] | {"horizontalStatus":"derivado","verticalStatus":"derivado","baseElevationM":286.25,"note":"Registro de líneas del PDF general con envolvente de 10,2 × 8,2 m. Estimación de trabajo de implantación de ±0,15 m, pendiente de CAD nativo; no constituye una precisión topográfica garantizada."} | {"Pset_WallCommon":{"IsExternal":{"value":true,"source":"ARQ-SB-20260710 · A101, A103 y alzados; elemento de la envolvente exterior identificada en planta","status":"known"}}} | {"boundingBoxM":{"min":[16.550382,33.606148,3.85],"max":[18.050023,33.909522,6.85]},"extentsM":[1.499641,0.303374,3.0],"meshSurfaceM2":9.899997,"meshVolumeM3":0.449999,"closedSolid":true,"basis":"Geometría triangulada releída del IFC; envolventes y magnitudes no contractuales."} | {"material":true,"document":true,"quantities":true,"containerGuid":"0Wh59pm9LO_einrwiq6Es1","containerName":"Planta baja"} | {"id":"architecture","name":"Arquitectura"} | {"profileId":"sandwich_panel","name":"Panel sándwich · chapa gris clara","materialName":"Panel sándwich de acero con núcleo de lana de roca","physicalMaterialStatus":"known","physicalMaterialSource":"ARQ-SB-20260710 · Arquitectura A103 / p. 5; A301Cuadro de materiales ; ARQ-OF-20260710 · A301 / p. 16, bloque correspondiente a la sala de bombas","appearanceStatus":"criterio_visual","appearanceBasis":"Interpretación visual del material documental; el acabado, tono y parámetros PBR no son una especificación contractual.","note":"La apariencia gráfica no modifica ni confirma la especificación física del material."} | {"elementId":"pump_house_0031","ifcGuid":"0kiJORbxrJ4Q_8F4x_DCPN","ifcClass":"IfcWall","buildingId":"pump_house","buildingName":"Sala de bombas contra incendios","sourceDocumentId":"ARQ-SB-20260710","sourceRepresentationKind":"documentary_mesh"} | {"layerId":"architecture","layerName":"Arquitectura","role":"Muro","basis":"Clasificación por función del elemento; no modifica las especificaciones documentales."} | architecture | {"profileId":"sandwich_panel","name":"Panel sándwich · chapa gris clara","status":"criterio_visual","basis":"Interpretación visual del material documental; el acabado, tono y parámetros PBR no son una especificación contractual.","physicalMaterialUnchanged":true} | ARQ-SB-20260710 · Arquitectura A103 / p. 5; A301Cuadro de materiales | Dimensiones contrastadas con los planos; reconstrucción geométrica a partir de documentación de diseño. | 0.1 | Muros segmentados con huecos reales para puertas y ventanas. | Envolvente exterior controlada por la planta de arquitectura; no se han modelado individualmente todas las capas de acabado. | Registro de líneas del PDF general con envolvente de 10,2 × 8,2 m. Estimación de trabajo de implantación de ±0,15 m, pendiente de CAD nativo; no constituye una precisión topográfica garantizada. | Arquitectura | ARQ-SB-20260710 · Arquitectura A103 / p. 5; A301Cuadro de materiales ; ARQ-OF-20260710 · A301 / p. 16, bloque correspondiente a la sala de bombas | 286.25 | Arquitectura | Panel sándwich · chapa gris clara | sandwich_panel | [0.85098,0.87451,0.87451] | 0.48 | 0.28 | Interpretación visual del material documental; el acabado, tono y parámetros PBR no son una especificación contractual. | Arquitectura; BIM · Arquitectura
Sala de bombas contra incendios · Panel sándwich de fachada con núcleo de lana de roca · eje B · tramo 10 | Planos de arquitectura de la sala de bombas contra incendios; Planos de arquitectura de la sala de bombas contra incendios | Panel sándwich de acero con núcleo de lana de roca | 1.3 × 0.1 × 1.1 | 287.45 | 288.55 | 0.143 | pump_house_0032 | yes | 1.3015 | 0.276133 | 1.1 | 3.34 | 0.143 | pump_house | Sala de bombas contra incendios | {"name":"Panel sándwich de acero con núcleo de lana de roca","source":"ARQ-SB-20260710 · Arquitectura A103 / p. 5; A301Cuadro de materiales ; ARQ-OF-20260710 · A301 / p. 16, bloque correspondiente a la sala de bombas","status":"known"} | {"documented":[{"label":"Espesor del muro","value":0.1,"unit":"m","source":"ARQ-SB-20260710 · Arquitectura A103 / p. 5; A301Cuadro de materiales ","status":"documentado"}],"geometry":[{"label":"Dimensiones de la caja local del elemento (X, Y, Z)","value":"1.3 × 0.1 × 1.1","unit":"m","source":"Malla triangulada del elemento en ejes locales del edificio","status":"derivado"},{"label":"Cota mínima absoluta de la malla","value":287.45,"unit":"m","source":"Malla de proyecto y origen altimétrico 285 m","status":"derivado"},{"label":"Cota máxima absoluta de la malla","value":288.55,"unit":"m","source":"Malla de proyecto y origen altimétrico 285 m","status":"derivado"},{"label":"Volumen geométrico bruto","value":0.143,"unit":"m³","source":"Malla cerrada del elemento","status":"derivado"}],"notes":["Las dimensiones documentadas proceden de anotaciones o cuadros; la caja y el volumen se calculan a partir de la malla.","El volumen es exclusivamente geométrico y bruto; no representa una medición neta de material ni una cantidad de compra."]} | {"documentId":"ARQ-SB-20260710","title":"Planos de arquitectura de la sala de bombas contra incendios","date":"2026-07-10","sheet":"Arquitectura A103 / p. 5; A301Cuadro de materiales "} | ["Envolvente exterior controlada por la planta de arquitectura; no se han modelado individualmente todas las capas de acabado.","Registro de líneas del PDF general con envolvente de 10,2 × 8,2 m. Estimación de trabajo de implantación de ±0,15 m, pendiente de CAD nativo; no constituye una precisión topográfica garantizada."] | {"horizontalStatus":"derivado","verticalStatus":"derivado","baseElevationM":286.25,"note":"Registro de líneas del PDF general con envolvente de 10,2 × 8,2 m. Estimación de trabajo de implantación de ±0,15 m, pendiente de CAD nativo; no constituye una precisión topográfica garantizada."} | {"Pset_WallCommon":{"IsExternal":{"value":true,"source":"ARQ-SB-20260710 · A101, A103 y alzados; elemento de la envolvente exterior identificada en planta","status":"known"}}} | {"boundingBoxM":{"min":[18.036403,33.429083,2.45],"max":[19.337908,33.705216,3.55]},"extentsM":[1.301505,0.276133,1.1],"meshSurfaceM2":3.339999,"meshVolumeM3":0.143,"closedSolid":true,"basis":"Geometría triangulada releída del IFC; envolventes y magnitudes no contractuales."} | {"material":true,"document":true,"quantities":true,"containerGuid":"0Wh59pm9LO_einrwiq6Es1","containerName":"Planta baja"} | {"id":"architecture","name":"Arquitectura"} | {"profileId":"sandwich_panel","name":"Panel sándwich · chapa gris clara","materialName":"Panel sándwich de acero con núcleo de lana de roca","physicalMaterialStatus":"known","physicalMaterialSource":"ARQ-SB-20260710 · Arquitectura A103 / p. 5; A301Cuadro de materiales ; ARQ-OF-20260710 · A301 / p. 16, bloque correspondiente a la sala de bombas","appearanceStatus":"criterio_visual","appearanceBasis":"Interpretación visual del material documental; el acabado, tono y parámetros PBR no son una especificación contractual.","note":"La apariencia gráfica no modifica ni confirma la especificación física del material."} | {"elementId":"pump_house_0032","ifcGuid":"3hfcoy_$fVIf_eG9j_dnvk","ifcClass":"IfcWall","buildingId":"pump_house","buildingName":"Sala de bombas contra incendios","sourceDocumentId":"ARQ-SB-20260710","sourceRepresentationKind":"documentary_mesh"} | {"layerId":"architecture","layerName":"Arquitectura","role":"Muro","basis":"Clasificación por función del elemento; no modifica las especificaciones documentales."} | architecture | {"profileId":"sandwich_panel","name":"Panel sándwich · chapa gris clara","status":"criterio_visual","basis":"Interpretación visual del material documental; el acabado, tono y parámetros PBR no son una especificación contractual.","physicalMaterialUnchanged":true} | ARQ-SB-20260710 · Arquitectura A103 / p. 5; A301Cuadro de materiales | Dimensiones contrastadas con los planos; reconstrucción geométrica a partir de documentación de diseño. | 0.1 | Muros segmentados con huecos reales para puertas y ventanas. | Envolvente exterior controlada por la planta de arquitectura; no se han modelado individualmente todas las capas de acabado. | Registro de líneas del PDF general con envolvente de 10,2 × 8,2 m. Estimación de trabajo de implantación de ±0,15 m, pendiente de CAD nativo; no constituye una precisión topográfica garantizada. | Arquitectura | ARQ-SB-20260710 · Arquitectura A103 / p. 5; A301Cuadro de materiales ; ARQ-OF-20260710 · A301 / p. 16, bloque correspondiente a la sala de bombas | 286.25 | Arquitectura | Panel sándwich · chapa gris clara | sandwich_panel | [0.85098,0.87451,0.87451] | 0.48 | 0.28 | Interpretación visual del material documental; el acabado, tono y parámetros PBR no son una especificación contractual. | Arquitectura; BIM · Arquitectura
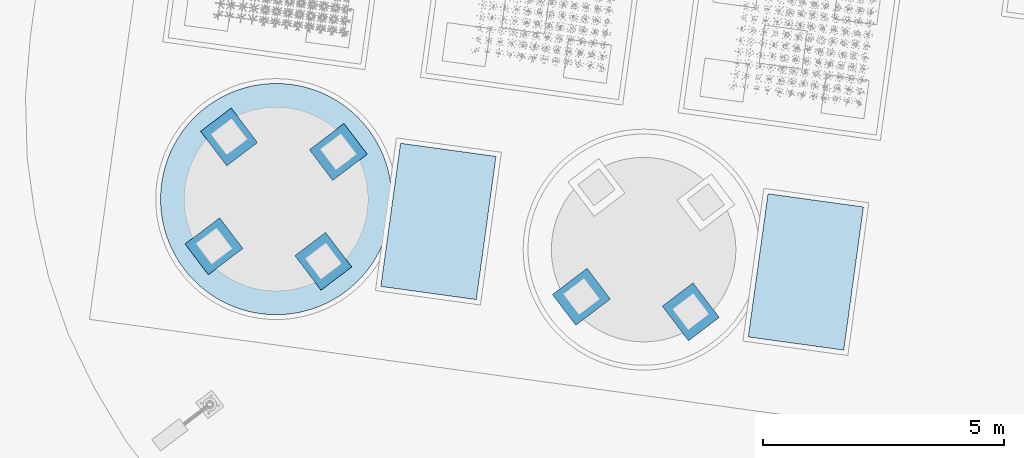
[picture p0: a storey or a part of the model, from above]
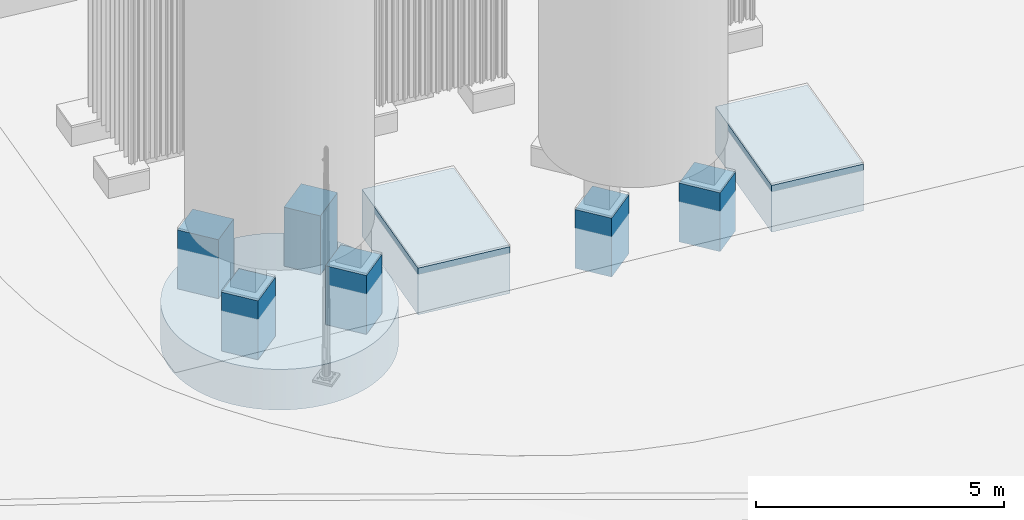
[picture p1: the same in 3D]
Properties of the parts of a building model (IFC4), part 116 of 134

# IfcWall (187)
Name | Document | Material = JH_Trazabilidad, Material = name | Dimensiones de la caja local del elemento (X, Y, Z) | Cota mínima absoluta de la malla (m) | Cota máxima absoluta de la malla (m) | Volumen geométrico bruto (m3) = Volumen geométrico (m³) | Reference = Identificador del elemento = Identificador | IsExternal | ExtensionX (m) | ExtensionY (m) | ExtensionZ (m) | SuperficieDeLaMalla (m2) | VolumenGeometrico (m3) = GrossVolume (m3) | buildingId | buildingName = Edificio | material | dimensions | JH_InformacionBIM, source = DocumentoFuente | issues = IncidenciasPendientes | positioning = PosicionYEstado | commonProperties | geometryMetrics | ifcAssociations | visualLayer | materialAppearance | visualizationIdentity | classification | layerId = IdentificadorCapa | appearance | Planos de referencia | Base geométrica | Espesor del muro (m) = Espesor del muro (m) | Tratamiento de los huecos | Representación de los acabados | Estado de la implantación | Disciplina | Referencia del material = JH_EvidenciaDeMaterial, source | Cota de planta baja terminada (m) | Capa BIM = NombreCapa | Acabado de visualización = Acabado | Perfil | ColorRGB | Rugosidad | Metallicidad | Referencia | Group | Discrepancia entre versiones
Sala de bombas contra incendios · Panel sándwich de fachada con núcleo de lana de roca · eje B · tramo 11 | Planos de arquitectura de la sala de bombas contra incendios; Planos de arquitectura de la sala de bombas contra incendios | Panel sándwich de acero con núcleo de lana de roca | 1.3 × 0.1 × 0.3 | 288.55 | 288.85 | 0.039 | pump_house_0033 | yes | 1.3015 | 0.276133 | 0.3 | 1.1 | 0.0389999 | pump_house | Sala de bombas contra incendios | {"name":"Panel sándwich de acero con núcleo de lana de roca","source":"ARQ-SB-20260710 · Arquitectura A103 / p. 5; A301Cuadro de materiales ; ARQ-OF-20260710 · A301 / p. 16, bloque correspondiente a la sala de bombas","status":"known"} | {"documented":[{"label":"Espesor del muro","value":0.1,"unit":"m","source":"ARQ-SB-20260710 · Arquitectura A103 / p. 5; A301Cuadro de materiales ","status":"documentado"}],"geometry":[{"label":"Dimensiones de la caja local del elemento (X, Y, Z)","value":"1.3 × 0.1 × 0.3","unit":"m","source":"Malla triangulada del elemento en ejes locales del edificio","status":"derivado"},{"label":"Cota mínima absoluta de la malla","value":288.55,"unit":"m","source":"Malla de proyecto y origen altimétrico 285 m","status":"derivado"},{"label":"Cota máxima absoluta de la malla","value":288.85,"unit":"m","source":"Malla de proyecto y origen altimétrico 285 m","status":"derivado"},{"label":"Volumen geométrico bruto","value":0.039,"unit":"m³","source":"Malla cerrada del elemento","status":"derivado"}],"notes":["Las dimensiones documentadas proceden de anotaciones o cuadros; la caja y el volumen se calculan a partir de la malla.","El volumen es exclusivamente geométrico y bruto; no representa una medición neta de material ni una cantidad de compra."]} | {"documentId":"ARQ-SB-20260710","title":"Planos de arquitectura de la sala de bombas contra incendios","date":"2026-07-10","sheet":"Arquitectura A103 / p. 5; A301Cuadro de materiales "} | ["Envolvente exterior controlada por la planta de arquitectura; no se han modelado individualmente todas las capas de acabado.","Registro de líneas del PDF general con envolvente de 10,2 × 8,2 m. Estimación de trabajo de implantación de ±0,15 m, pendiente de CAD nativo; no constituye una precisión topográfica garantizada."] | {"horizontalStatus":"derivado","verticalStatus":"derivado","baseElevationM":286.25,"note":"Registro de líneas del PDF general con envolvente de 10,2 × 8,2 m. Estimación de trabajo de implantación de ±0,15 m, pendiente de CAD nativo; no constituye una precisión topográfica garantizada."} | {"Pset_WallCommon":{"IsExternal":{"value":true,"source":"ARQ-SB-20260710 · A101, A103 y alzados; elemento de la envolvente exterior identificada en planta","status":"known"}}} | {"boundingBoxM":{"min":[18.036403,33.429083,3.55],"max":[19.337908,33.705216,3.85]},"extentsM":[1.301505,0.276133,0.3],"meshSurfaceM2":1.1,"meshVolumeM3":0.039,"closedSolid":true,"basis":"Geometría triangulada releída del IFC; envolventes y magnitudes no contractuales."} | {"material":true,"document":true,"quantities":true,"containerGuid":"0Wh59pm9LO_einrwiq6Es1","containerName":"Planta baja"} | {"id":"architecture","name":"Arquitectura"} | {"profileId":"sandwich_panel","name":"Panel sándwich · chapa gris clara","materialName":"Panel sándwich de acero con núcleo de lana de roca","physicalMaterialStatus":"known","physicalMaterialSource":"ARQ-SB-20260710 · Arquitectura A103 / p. 5; A301Cuadro de materiales ; ARQ-OF-20260710 · A301 / p. 16, bloque correspondiente a la sala de bombas","appearanceStatus":"criterio_visual","appearanceBasis":"Interpretación visual del material documental; el acabado, tono y parámetros PBR no son una especificación contractual.","note":"La apariencia gráfica no modifica ni confirma la especificación física del material."} | {"elementId":"pump_house_0033","ifcGuid":"2nsmt$SZbN8x0fa1sxnT2k","ifcClass":"IfcWall","buildingId":"pump_house","buildingName":"Sala de bombas contra incendios","sourceDocumentId":"ARQ-SB-20260710","sourceRepresentationKind":"documentary_mesh"} | {"layerId":"architecture","layerName":"Arquitectura","role":"Muro","basis":"Clasificación por función del elemento; no modifica las especificaciones documentales."} | architecture | {"profileId":"sandwich_panel","name":"Panel sándwich · chapa gris clara","status":"criterio_visual","basis":"Interpretación visual del material documental; el acabado, tono y parámetros PBR no son una especificación contractual.","physicalMaterialUnchanged":true} | ARQ-SB-20260710 · Arquitectura A103 / p. 5; A301Cuadro de materiales | Dimensiones contrastadas con los planos; reconstrucción geométrica a partir de documentación de diseño. | 0.1 | Muros segmentados con huecos reales para puertas y ventanas. | Envolvente exterior controlada por la planta de arquitectura; no se han modelado individualmente todas las capas de acabado. | Registro de líneas del PDF general con envolvente de 10,2 × 8,2 m. Estimación de trabajo de implantación de ±0,15 m, pendiente de CAD nativo; no constituye una precisión topográfica garantizada. | Arquitectura | ARQ-SB-20260710 · Arquitectura A103 / p. 5; A301Cuadro de materiales ; ARQ-OF-20260710 · A301 / p. 16, bloque correspondiente a la sala de bombas | 286.25 | Arquitectura | Panel sándwich · chapa gris clara | sandwich_panel | [0.85098,0.87451,0.87451] | 0.48 | 0.28 | Interpretación visual del material documental; el acabado, tono y parámetros PBR no son una especificación contractual. | Arquitectura; BIM · Arquitectura
Sala de bombas contra incendios · Panel sándwich de fachada con núcleo de lana de roca · eje B · tramo 12 | Planos de arquitectura de la sala de bombas contra incendios; Planos de arquitectura de la sala de bombas contra incendios | Panel sándwich de acero con núcleo de lana de roca | 1.3 × 0.1 × 3 | 288.85 | 291.85 | 0.39 | pump_house_0034 | yes | 1.3015 | 0.276133 | 3 | 8.66 | 0.389999 | pump_house | Sala de bombas contra incendios | {"name":"Panel sándwich de acero con núcleo de lana de roca","source":"ARQ-SB-20260710 · Arquitectura A103 / p. 5; A301Cuadro de materiales ; ARQ-OF-20260710 · A301 / p. 16, bloque correspondiente a la sala de bombas","status":"known"} | {"documented":[{"label":"Espesor del muro","value":0.1,"unit":"m","source":"ARQ-SB-20260710 · Arquitectura A103 / p. 5; A301Cuadro de materiales ","status":"documentado"}],"geometry":[{"label":"Dimensiones de la caja local del elemento (X, Y, Z)","value":"1.3 × 0.1 × 3","unit":"m","source":"Malla triangulada del elemento en ejes locales del edificio","status":"derivado"},{"label":"Cota mínima absoluta de la malla","value":288.85,"unit":"m","source":"Malla de proyecto y origen altimétrico 285 m","status":"derivado"},{"label":"Cota máxima absoluta de la malla","value":291.85,"unit":"m","source":"Malla de proyecto y origen altimétrico 285 m","status":"derivado"},{"label":"Volumen geométrico bruto","value":0.39,"unit":"m³","source":"Malla cerrada del elemento","status":"derivado"}],"notes":["Las dimensiones documentadas proceden de anotaciones o cuadros; la caja y el volumen se calculan a partir de la malla.","El volumen es exclusivamente geométrico y bruto; no representa una medición neta de material ni una cantidad de compra."]} | {"documentId":"ARQ-SB-20260710","title":"Planos de arquitectura de la sala de bombas contra incendios","date":"2026-07-10","sheet":"Arquitectura A103 / p. 5; A301Cuadro de materiales "} | ["Envolvente exterior controlada por la planta de arquitectura; no se han modelado individualmente todas las capas de acabado.","Registro de líneas del PDF general con envolvente de 10,2 × 8,2 m. Estimación de trabajo de implantación de ±0,15 m, pendiente de CAD nativo; no constituye una precisión topográfica garantizada."] | {"horizontalStatus":"derivado","verticalStatus":"derivado","baseElevationM":286.25,"note":"Registro de líneas del PDF general con envolvente de 10,2 × 8,2 m. Estimación de trabajo de implantación de ±0,15 m, pendiente de CAD nativo; no constituye una precisión topográfica garantizada."} | {"Pset_WallCommon":{"IsExternal":{"value":true,"source":"ARQ-SB-20260710 · A101, A103 y alzados; elemento de la envolvente exterior identificada en planta","status":"known"}}} | {"boundingBoxM":{"min":[18.036403,33.429083,3.85],"max":[19.337908,33.705216,6.85]},"extentsM":[1.301505,0.276133,3.0],"meshSurfaceM2":8.659998,"meshVolumeM3":0.389999,"closedSolid":true,"basis":"Geometría triangulada releída del IFC; envolventes y magnitudes no contractuales."} | {"material":true,"document":true,"quantities":true,"containerGuid":"0Wh59pm9LO_einrwiq6Es1","containerName":"Planta baja"} | {"id":"architecture","name":"Arquitectura"} | {"profileId":"sandwich_panel","name":"Panel sándwich · chapa gris clara","materialName":"Panel sándwich de acero con núcleo de lana de roca","physicalMaterialStatus":"known","physicalMaterialSource":"ARQ-SB-20260710 · Arquitectura A103 / p. 5; A301Cuadro de materiales ; ARQ-OF-20260710 · A301 / p. 16, bloque correspondiente a la sala de bombas","appearanceStatus":"criterio_visual","appearanceBasis":"Interpretación visual del material documental; el acabado, tono y parámetros PBR no son una especificación contractual.","note":"La apariencia gráfica no modifica ni confirma la especificación física del material."} | {"elementId":"pump_house_0034","ifcGuid":"3duWCqGIjSFvPv$hKsXoJq","ifcClass":"IfcWall","buildingId":"pump_house","buildingName":"Sala de bombas contra incendios","sourceDocumentId":"ARQ-SB-20260710","sourceRepresentationKind":"documentary_mesh"} | {"layerId":"architecture","layerName":"Arquitectura","role":"Muro","basis":"Clasificación por función del elemento; no modifica las especificaciones documentales."} | architecture | {"profileId":"sandwich_panel","name":"Panel sándwich · chapa gris clara","status":"criterio_visual","basis":"Interpretación visual del material documental; el acabado, tono y parámetros PBR no son una especificación contractual.","physicalMaterialUnchanged":true} | ARQ-SB-20260710 · Arquitectura A103 / p. 5; A301Cuadro de materiales | Dimensiones contrastadas con los planos; reconstrucción geométrica a partir de documentación de diseño. | 0.1 | Muros segmentados con huecos reales para puertas y ventanas. | Envolvente exterior controlada por la planta de arquitectura; no se han modelado individualmente todas las capas de acabado. | Registro de líneas del PDF general con envolvente de 10,2 × 8,2 m. Estimación de trabajo de implantación de ±0,15 m, pendiente de CAD nativo; no constituye una precisión topográfica garantizada. | Arquitectura | ARQ-SB-20260710 · Arquitectura A103 / p. 5; A301Cuadro de materiales ; ARQ-OF-20260710 · A301 / p. 16, bloque correspondiente a la sala de bombas | 286.25 | Arquitectura | Panel sándwich · chapa gris clara | sandwich_panel | [0.85098,0.87451,0.87451] | 0.48 | 0.28 | Interpretación visual del material documental; el acabado, tono y parámetros PBR no son una especificación contractual. | Arquitectura; BIM · Arquitectura
Sala de bombas contra incendios · Zócalo de hormigón · eje 1 · tramo 01 | Planos de arquitectura de la sala de bombas contra incendios; Planos de arquitectura de la sala de bombas contra incendios | Hormigón prefabricado macizo | 0.2 × 7.8 × 1.2 | 286.25 | 287.45 | 1.872 | pump_house_0035 | yes | 1.26053 | 7.75455 | 1.2 | 22.32 | 1.872 | pump_house | Sala de bombas contra incendios | {"name":"Hormigón prefabricado macizo","source":"ARQ-SB-20260710 · Arquitectura A103 / p. 5; Estructura A201 / p. 4","status":"known"} | {"documented":[{"label":"Espesor del muro","value":0.2,"unit":"m","source":"ARQ-SB-20260710 · Arquitectura A103 / p. 5; Estructura A201 / p. 4","status":"documentado"}],"geometry":[{"label":"Dimensiones de la caja local del elemento (X, Y, Z)","value":"0.2 × 7.8 × 1.2","unit":"m","source":"Malla triangulada del elemento en ejes locales del edificio","status":"derivado"},{"label":"Cota mínima absoluta de la malla","value":286.25,"unit":"m","source":"Malla de proyecto y origen altimétrico 285 m","status":"derivado"},{"label":"Cota máxima absoluta de la malla","value":287.45,"unit":"m","source":"Malla de proyecto y origen altimétrico 285 m","status":"derivado"},{"label":"Volumen geométrico bruto","value":1.872,"unit":"m³","source":"Malla cerrada del elemento","status":"derivado"}],"notes":["Las dimensiones documentadas proceden de anotaciones o cuadros; la caja y el volumen se calculan a partir de la malla.","El volumen es exclusivamente geométrico y bruto; no representa una medición neta de material ni una cantidad de compra."]} | {"documentId":"ARQ-SB-20260710","title":"Planos de arquitectura de la sala de bombas contra incendios","date":"2026-07-10","sheet":"Arquitectura A103 / p. 5; Estructura A201 / p. 4"} | ["Envolvente exterior controlada por la planta de arquitectura; no se han modelado individualmente todas las capas de acabado.","Registro de líneas del PDF general con envolvente de 10,2 × 8,2 m. Estimación de trabajo de implantación de ±0,15 m, pendiente de CAD nativo; no constituye una precisión topográfica garantizada."] | {"horizontalStatus":"derivado","verticalStatus":"derivado","baseElevationM":286.25,"note":"Registro de líneas del PDF general con envolvente de 10,2 × 8,2 m. Estimación de trabajo de implantación de ±0,15 m, pendiente de CAD nativo; no constituye una precisión topográfica garantizada."} | {"Pset_WallCommon":{"IsExternal":{"value":true,"source":"ARQ-SB-20260710 · A101, A103 y alzados; elemento de la envolvente exterior identificada en planta","status":"known"}}} | {"boundingBoxM":{"min":[8.143333,26.964744,1.25],"max":[9.403859,34.719295,2.45]},"extentsM":[1.260526,7.754551,1.2],"meshSurfaceM2":22.319996,"meshVolumeM3":1.871999,"closedSolid":true,"basis":"Geometría triangulada releída del IFC; envolventes y magnitudes no contractuales."} | {"material":true,"document":true,"quantities":true,"containerGuid":"0Wh59pm9LO_einrwiq6Es1","containerName":"Planta baja"} | {"id":"architecture","name":"Arquitectura"} | {"profileId":"concrete_precast","name":"Hormigón prefabricado","materialName":"Hormigón prefabricado macizo","physicalMaterialStatus":"known","physicalMaterialSource":"ARQ-SB-20260710 · Arquitectura A103 / p. 5; Estructura A201 / p. 4","appearanceStatus":"criterio_visual","appearanceBasis":"Interpretación visual del material documental; el acabado, tono y parámetros PBR no son una especificación contractual.","note":"La apariencia gráfica no modifica ni confirma la especificación física del material."} | {"elementId":"pump_house_0035","ifcGuid":"3YtovDkALPKhkyxTXe8kyK","ifcClass":"IfcWall","buildingId":"pump_house","buildingName":"Sala de bombas contra incendios","sourceDocumentId":"ARQ-SB-20260710","sourceRepresentationKind":"documentary_mesh"} | {"layerId":"architecture","layerName":"Arquitectura","role":"Muro","basis":"Clasificación por función del elemento; no modifica las especificaciones documentales."} | architecture | {"profileId":"concrete_precast","name":"Hormigón prefabricado","status":"criterio_visual","basis":"Interpretación visual del material documental; el acabado, tono y parámetros PBR no son una especificación contractual.","physicalMaterialUnchanged":true} | ARQ-SB-20260710 · Arquitectura A103 / p. 5; Estructura A201 / p. 4 | Dimensiones contrastadas con los planos; reconstrucción geométrica a partir de documentación de diseño. | 0.2 | Muros segmentados con huecos reales para puertas y ventanas. | Envolvente exterior controlada por la planta de arquitectura; no se han modelado individualmente todas las capas de acabado. | Registro de líneas del PDF general con envolvente de 10,2 × 8,2 m. Estimación de trabajo de implantación de ±0,15 m, pendiente de CAD nativo; no constituye una precisión topográfica garantizada. | Arquitectura | ARQ-SB-20260710 · Arquitectura A103 / p. 5; Estructura A201 / p. 4 | 286.25 | Arquitectura | Hormigón prefabricado | concrete_precast | [0.756863,0.752941,0.717647] | 0.86 | 0 | Interpretación visual del material documental; el acabado, tono y parámetros PBR no son una especificación contractual. | Arquitectura; BIM · Arquitectura
Sala de bombas contra incendios · Panel sándwich de fachada con núcleo de lana de roca · eje 1 · tramo 01 | Planos de arquitectura de la sala de bombas contra incendios; Planos de arquitectura de la sala de bombas contra incendios | Panel sándwich de acero con núcleo de lana de roca | 0.1 × 7.8 × 4.4 | 287.45 | 291.85 | 3.432 | pump_house_0036 | yes | 1.16146 | 7.74093 | 4.4 | 71.08 | 3.432 | pump_house | Sala de bombas contra incendios | {"name":"Panel sándwich de acero con núcleo de lana de roca","source":"ARQ-SB-20260710 · Arquitectura A103 / p. 5; A301Cuadro de materiales ; ARQ-OF-20260710 · A301 / p. 16, bloque correspondiente a la sala de bombas","status":"known"} | {"documented":[{"label":"Espesor del muro","value":0.1,"unit":"m","source":"ARQ-SB-20260710 · Arquitectura A103 / p. 5; A301Cuadro de materiales ","status":"documentado"}],"geometry":[{"label":"Dimensiones de la caja local del elemento (X, Y, Z)","value":"0.1 × 7.8 × 4.4","unit":"m","source":"Malla triangulada del elemento en ejes locales del edificio","status":"derivado"},{"label":"Cota mínima absoluta de la malla","value":287.45,"unit":"m","source":"Malla de proyecto y origen altimétrico 285 m","status":"derivado"},{"label":"Cota máxima absoluta de la malla","value":291.85,"unit":"m","source":"Malla de proyecto y origen altimétrico 285 m","status":"derivado"},{"label":"Volumen geométrico bruto","value":3.432,"unit":"m³","source":"Malla cerrada del elemento","status":"derivado"}],"notes":["Las dimensiones documentadas proceden de anotaciones o cuadros; la caja y el volumen se calculan a partir de la malla.","El volumen es exclusivamente geométrico y bruto; no representa una medición neta de material ni una cantidad de compra."]} | {"documentId":"ARQ-SB-20260710","title":"Planos de arquitectura de la sala de bombas contra incendios","date":"2026-07-10","sheet":"Arquitectura A103 / p. 5; A301Cuadro de materiales "} | ["Envolvente exterior controlada por la planta de arquitectura; no se han modelado individualmente todas las capas de acabado.","Registro de líneas del PDF general con envolvente de 10,2 × 8,2 m. Estimación de trabajo de implantación de ±0,15 m, pendiente de CAD nativo; no constituye una precisión topográfica garantizada."] | {"horizontalStatus":"derivado","verticalStatus":"derivado","baseElevationM":286.25,"note":"Registro de líneas del PDF general con envolvente de 10,2 × 8,2 m. Estimación de trabajo de implantación de ±0,15 m, pendiente de CAD nativo; no constituye una precisión topográfica garantizada."} | {"Pset_WallCommon":{"IsExternal":{"value":true,"source":"ARQ-SB-20260710 · A101, A103 y alzados; elemento de la envolvente exterior identificada en planta","status":"known"}}} | {"boundingBoxM":{"min":[8.143333,26.978364,2.45],"max":[9.304791,34.719295,6.85]},"extentsM":[1.161458,7.740931,4.4],"meshSurfaceM2":71.079998,"meshVolumeM3":3.431998,"closedSolid":true,"basis":"Geometría triangulada releída del IFC; envolventes y magnitudes no contractuales."} | {"material":true,"document":true,"quantities":true,"containerGuid":"0Wh59pm9LO_einrwiq6Es1","containerName":"Planta baja"} | {"id":"architecture","name":"Arquitectura"} | {"profileId":"sandwich_panel","name":"Panel sándwich · chapa gris clara","materialName":"Panel sándwich de acero con núcleo de lana de roca","physicalMaterialStatus":"known","physicalMaterialSource":"ARQ-SB-20260710 · Arquitectura A103 / p. 5; A301Cuadro de materiales ; ARQ-OF-20260710 · A301 / p. 16, bloque correspondiente a la sala de bombas","appearanceStatus":"criterio_visual","appearanceBasis":"Interpretación visual del material documental; el acabado, tono y parámetros PBR no son una especificación contractual.","note":"La apariencia gráfica no modifica ni confirma la especificación física del material."} | {"elementId":"pump_house_0036","ifcGuid":"35j38bUbzGJAUyxXLUzfz5","ifcClass":"IfcWall","buildingId":"pump_house","buildingName":"Sala de bombas contra incendios","sourceDocumentId":"ARQ-SB-20260710","sourceRepresentationKind":"documentary_mesh"} | {"layerId":"architecture","layerName":"Arquitectura","role":"Muro","basis":"Clasificación por función del elemento; no modifica las especificaciones documentales."} | architecture | {"profileId":"sandwich_panel","name":"Panel sándwich · chapa gris clara","status":"criterio_visual","basis":"Interpretación visual del material documental; el acabado, tono y parámetros PBR no son una especificación contractual.","physicalMaterialUnchanged":true} | ARQ-SB-20260710 · Arquitectura A103 / p. 5; A301Cuadro de materiales | Dimensiones contrastadas con los planos; reconstrucción geométrica a partir de documentación de diseño. | 0.1 | Muros segmentados con huecos reales para puertas y ventanas. | Envolvente exterior controlada por la planta de arquitectura; no se han modelado individualmente todas las capas de acabado. | Registro de líneas del PDF general con envolvente de 10,2 × 8,2 m. Estimación de trabajo de implantación de ±0,15 m, pendiente de CAD nativo; no constituye una precisión topográfica garantizada. | Arquitectura | ARQ-SB-20260710 · Arquitectura A103 / p. 5; A301Cuadro de materiales ; ARQ-OF-20260710 · A301 / p. 16, bloque correspondiente a la sala de bombas | 286.25 | Arquitectura | Panel sándwich · chapa gris clara | sandwich_panel | [0.85098,0.87451,0.87451] | 0.48 | 0.28 | Interpretación visual del material documental; el acabado, tono y parámetros PBR no son una especificación contractual. | Arquitectura; BIM · Arquitectura
Sala de bombas contra incendios · Zócalo de hormigón · eje 2 · tramo 01 | Planos de arquitectura de la sala de bombas contra incendios; Planos de arquitectura de la sala de bombas contra incendios | Hormigón prefabricado macizo | 0.2 × 7.8 × 1.2 | 286.25 | 287.45 | 1.872 | pump_house_0037 | yes | 1.26053 | 7.75455 | 1.2 | 22.32 | 1.872 | pump_house | Sala de bombas contra incendios | {"name":"Hormigón prefabricado macizo","source":"ARQ-SB-20260710 · Arquitectura A103 / p. 5; Estructura A201 / p. 4","status":"known"} | {"documented":[{"label":"Espesor del muro","value":0.2,"unit":"m","source":"ARQ-SB-20260710 · Arquitectura A103 / p. 5; Estructura A201 / p. 4","status":"documentado"}],"geometry":[{"label":"Dimensiones de la caja local del elemento (X, Y, Z)","value":"0.2 × 7.8 × 1.2","unit":"m","source":"Malla triangulada del elemento en ejes locales del edificio","status":"derivado"},{"label":"Cota mínima absoluta de la malla","value":286.25,"unit":"m","source":"Malla de proyecto y origen altimétrico 285 m","status":"derivado"},{"label":"Cota máxima absoluta de la malla","value":287.45,"unit":"m","source":"Malla de proyecto y origen altimétrico 285 m","status":"derivado"},{"label":"Volumen geométrico bruto","value":1.872,"unit":"m³","source":"Malla cerrada del elemento","status":"derivado"}],"notes":["Las dimensiones documentadas proceden de anotaciones o cuadros; la caja y el volumen se calculan a partir de la malla.","El volumen es exclusivamente geométrico y bruto; no representa una medición neta de material ni una cantidad de compra."]} | {"documentId":"ARQ-SB-20260710","title":"Planos de arquitectura de la sala de bombas contra incendios","date":"2026-07-10","sheet":"Arquitectura A103 / p. 5; Estructura A201 / p. 4"} | ["Envolvente exterior controlada por la planta de arquitectura; no se han modelado individualmente todas las capas de acabado.","Registro de líneas del PDF general con envolvente de 10,2 × 8,2 m. Estimación de trabajo de implantación de ±0,15 m, pendiente de CAD nativo; no constituye una precisión topográfica garantizada."] | {"horizontalStatus":"derivado","verticalStatus":"derivado","baseElevationM":286.25,"note":"Registro de líneas del PDF general con envolvente de 10,2 × 8,2 m. Estimación de trabajo de implantación de ±0,15 m, pendiente de CAD nativo; no constituye una precisión topográfica garantizada."} | {"Pset_WallCommon":{"IsExternal":{"value":true,"source":"ARQ-SB-20260710 · A101, A103 y alzados; elemento de la envolvente exterior identificada en planta","status":"known"}}} | {"boundingBoxM":{"min":[18.050141,25.602705,1.25],"max":[19.310667,33.357256,2.45]},"extentsM":[1.260526,7.754551,1.2],"meshSurfaceM2":22.319996,"meshVolumeM3":1.871999,"closedSolid":true,"basis":"Geometría triangulada releída del IFC; envolventes y magnitudes no contractuales."} | {"material":true,"document":true,"quantities":true,"containerGuid":"0Wh59pm9LO_einrwiq6Es1","containerName":"Planta baja"} | {"id":"architecture","name":"Arquitectura"} | {"profileId":"concrete_precast","name":"Hormigón prefabricado","materialName":"Hormigón prefabricado macizo","physicalMaterialStatus":"known","physicalMaterialSource":"ARQ-SB-20260710 · Arquitectura A103 / p. 5; Estructura A201 / p. 4","appearanceStatus":"criterio_visual","appearanceBasis":"Interpretación visual del material documental; el acabado, tono y parámetros PBR no son una especificación contractual.","note":"La apariencia gráfica no modifica ni confirma la especificación física del material."} | {"elementId":"pump_house_0037","ifcGuid":"2PLTLuV0nVt8ko8HGNj84D","ifcClass":"IfcWall","buildingId":"pump_house","buildingName":"Sala de bombas contra incendios","sourceDocumentId":"ARQ-SB-20260710","sourceRepresentationKind":"documentary_mesh"} | {"layerId":"architecture","layerName":"Arquitectura","role":"Muro","basis":"Clasificación por función del elemento; no modifica las especificaciones documentales."} | architecture | {"profileId":"concrete_precast","name":"Hormigón prefabricado","status":"criterio_visual","basis":"Interpretación visual del material documental; el acabado, tono y parámetros PBR no son una especificación contractual.","physicalMaterialUnchanged":true} | ARQ-SB-20260710 · Arquitectura A103 / p. 5; Estructura A201 / p. 4 | Dimensiones contrastadas con los planos; reconstrucción geométrica a partir de documentación de diseño. | 0.2 | Muros segmentados con huecos reales para puertas y ventanas. | Envolvente exterior controlada por la planta de arquitectura; no se han modelado individualmente todas las capas de acabado. | Registro de líneas del PDF general con envolvente de 10,2 × 8,2 m. Estimación de trabajo de implantación de ±0,15 m, pendiente de CAD nativo; no constituye una precisión topográfica garantizada. | Arquitectura | ARQ-SB-20260710 · Arquitectura A103 / p. 5; Estructura A201 / p. 4 | 286.25 | Arquitectura | Hormigón prefabricado | concrete_precast | [0.756863,0.752941,0.717647] | 0.86 | 0 | Interpretación visual del material documental; el acabado, tono y parámetros PBR no son una especificación contractual. | Arquitectura; BIM · Arquitectura
Sala de bombas contra incendios · Panel sándwich de fachada con núcleo de lana de roca · eje 2 · tramo 01 | Planos de arquitectura de la sala de bombas contra incendios; Planos de arquitectura de la sala de bombas contra incendios | Panel sándwich de acero con núcleo de lana de roca | 0.1 × 7.8 × 4.4 | 287.45 | 291.85 | 3.432 | pump_house_0038 | yes | 1.16146 | 7.74093 | 4.4 | 71.08 | 3.432 | pump_house | Sala de bombas contra incendios | {"name":"Panel sándwich de acero con núcleo de lana de roca","source":"ARQ-SB-20260710 · Arquitectura A103 / p. 5; A301Cuadro de materiales ; ARQ-OF-20260710 · A301 / p. 16, bloque correspondiente a la sala de bombas","status":"known"} | {"documented":[{"label":"Espesor del muro","value":0.1,"unit":"m","source":"ARQ-SB-20260710 · Arquitectura A103 / p. 5; A301Cuadro de materiales ","status":"documentado"}],"geometry":[{"label":"Dimensiones de la caja local del elemento (X, Y, Z)","value":"0.1 × 7.8 × 4.4","unit":"m","source":"Malla triangulada del elemento en ejes locales del edificio","status":"derivado"},{"label":"Cota mínima absoluta de la malla","value":287.45,"unit":"m","source":"Malla de proyecto y origen altimétrico 285 m","status":"derivado"},{"label":"Cota máxima absoluta de la malla","value":291.85,"unit":"m","source":"Malla de proyecto y origen altimétrico 285 m","status":"derivado"},{"label":"Volumen geométrico bruto","value":3.432,"unit":"m³","source":"Malla cerrada del elemento","status":"derivado"}],"notes":["Las dimensiones documentadas proceden de anotaciones o cuadros; la caja y el volumen se calculan a partir de la malla.","El volumen es exclusivamente geométrico y bruto; no representa una medición neta de material ni una cantidad de compra."]} | {"documentId":"ARQ-SB-20260710","title":"Planos de arquitectura de la sala de bombas contra incendios","date":"2026-07-10","sheet":"Arquitectura A103 / p. 5; A301Cuadro de materiales "} | ["Envolvente exterior controlada por la planta de arquitectura; no se han modelado individualmente todas las capas de acabado.","Registro de líneas del PDF general con envolvente de 10,2 × 8,2 m. Estimación de trabajo de implantación de ±0,15 m, pendiente de CAD nativo; no constituye una precisión topográfica garantizada."] | {"horizontalStatus":"derivado","verticalStatus":"derivado","baseElevationM":286.25,"note":"Registro de líneas del PDF general con envolvente de 10,2 × 8,2 m. Estimación de trabajo de implantación de ±0,15 m, pendiente de CAD nativo; no constituye una precisión topográfica garantizada."} | {"Pset_WallCommon":{"IsExternal":{"value":true,"source":"ARQ-SB-20260710 · A101, A103 y alzados; elemento de la envolvente exterior identificada en planta","status":"known"}}} | {"boundingBoxM":{"min":[18.149209,25.602705,2.45],"max":[19.310667,33.343636,6.85]},"extentsM":[1.161458,7.740931,4.4],"meshSurfaceM2":71.079998,"meshVolumeM3":3.431998,"closedSolid":true,"basis":"Geometría triangulada releída del IFC; envolventes y magnitudes no contractuales."} | {"material":true,"document":true,"quantities":true,"containerGuid":"0Wh59pm9LO_einrwiq6Es1","containerName":"Planta baja"} | {"id":"architecture","name":"Arquitectura"} | {"profileId":"sandwich_panel","name":"Panel sándwich · chapa gris clara","materialName":"Panel sándwich de acero con núcleo de lana de roca","physicalMaterialStatus":"known","physicalMaterialSource":"ARQ-SB-20260710 · Arquitectura A103 / p. 5; A301Cuadro de materiales ; ARQ-OF-20260710 · A301 / p. 16, bloque correspondiente a la sala de bombas","appearanceStatus":"criterio_visual","appearanceBasis":"Interpretación visual del material documental; el acabado, tono y parámetros PBR no son una especificación contractual.","note":"La apariencia gráfica no modifica ni confirma la especificación física del material."} | {"elementId":"pump_house_0038","ifcGuid":"2NMIIAcc9Tgfil7YX4ZQ3c","ifcClass":"IfcWall","buildingId":"pump_house","buildingName":"Sala de bombas contra incendios","sourceDocumentId":"ARQ-SB-20260710","sourceRepresentationKind":"documentary_mesh"} | {"layerId":"architecture","layerName":"Arquitectura","role":"Muro","basis":"Clasificación por función del elemento; no modifica las especificaciones documentales."} | architecture | {"profileId":"sandwich_panel","name":"Panel sándwich · chapa gris clara","status":"criterio_visual","basis":"Interpretación visual del material documental; el acabado, tono y parámetros PBR no son una especificación contractual.","physicalMaterialUnchanged":true} | ARQ-SB-20260710 · Arquitectura A103 / p. 5; A301Cuadro de materiales | Dimensiones contrastadas con los planos; reconstrucción geométrica a partir de documentación de diseño. | 0.1 | Muros segmentados con huecos reales para puertas y ventanas. | Envolvente exterior controlada por la planta de arquitectura; no se han modelado individualmente todas las capas de acabado. | Registro de líneas del PDF general con envolvente de 10,2 × 8,2 m. Estimación de trabajo de implantación de ±0,15 m, pendiente de CAD nativo; no constituye una precisión topográfica garantizada. | Arquitectura | ARQ-SB-20260710 · Arquitectura A103 / p. 5; A301Cuadro de materiales ; ARQ-OF-20260710 · A301 / p. 16, bloque correspondiente a la sala de bombas | 286.25 | Arquitectura | Panel sándwich · chapa gris clara | sandwich_panel | [0.85098,0.87451,0.87451] | 0.48 | 0.28 | Interpretación visual del material documental; el acabado, tono y parámetros PBR no son una especificación contractual. | Arquitectura; BIM · Arquitectura
Sala de bombas contra incendios · muro de cimentación de 200 mm · eje A | Planos de estructura de la sala de bombas contra incendios | Hormigón armado | 10.2 × 0.2 × 1.5 | 284.75 | 286.25 | 3.06 | pump_house_0044 |  | 10.1322 | 1.58742 | 1.5 | 35.28 | 3.06 | pump_house | Sala de bombas contra incendios | {"name":"Hormigón armado","source":"EST-SB-20260710 · Estructura A201 / p. 4","status":"known"} | {"documented":[{"label":"Espesor","value":0.2,"unit":"m","source":"EST-SB-20260710 · Estructura A201 / p. 4","status":"provisional"},{"label":"Cota inferior absoluta","value":284.75,"unit":"m","source":"EST-SB-20260710 · Estructura A201 / p. 4","status":"documentado"},{"label":"Cota superior absoluta","value":286.25,"unit":"m","source":"EST-SB-20260710 · Estructura A201 / p. 4","status":"documentado"}],"geometry":[{"label":"Dimensiones de la caja local del elemento (X, Y, Z)","value":"10.2 × 0.2 × 1.5","unit":"m","source":"Malla triangulada del elemento en ejes locales del edificio","status":"derivado"},{"label":"Cota mínima absoluta de la malla","value":284.75,"unit":"m","source":"Malla de proyecto y origen altimétrico 285 m","status":"derivado"},{"label":"Cota máxima absoluta de la malla","value":286.25,"unit":"m","source":"Malla de proyecto y origen altimétrico 285 m","status":"derivado"},{"label":"Volumen geométrico bruto","value":3.06,"unit":"m³","source":"Malla cerrada del elemento","status":"derivado"}],"notes":["Las dimensiones documentadas proceden de anotaciones o cuadros; la caja y el volumen se calculan a partir de la malla.","El volumen es exclusivamente geométrico y bruto; no representa una medición neta de material ni una cantidad de compra."]} | {"documentId":"EST-SB-20260710","title":"Planos de estructura de la sala de bombas contra incendios","date":"2026-07-10","sheet":"Estructura A201 / p. 4"} | ["Sistema de ejecución del muro, prefabricado o in situ, pendiente de aclaración.","Registro de líneas del PDF general con envolvente de 10,2 × 8,2 m. Estimación de trabajo de implantación de ±0,15 m, pendiente de CAD nativo; no constituye una precisión topográfica garantizada."] | {"horizontalStatus":"derivado","verticalStatus":"derivado","baseElevationM":286.25,"note":"Registro de líneas del PDF general con envolvente de 10,2 × 8,2 m. Estimación de trabajo de implantación de ±0,15 m, pendiente de CAD nativo; no constituye una precisión topográfica garantizada."} |  | {"boundingBoxM":{"min":[8.116092,25.404569,-0.25],"max":[18.248277,26.991985,1.25]},"extentsM":[10.132185,1.587416,1.5],"meshSurfaceM2":35.279996,"meshVolumeM3":3.059998,"closedSolid":true,"basis":"Geometría triangulada releída del IFC; envolventes y magnitudes no contractuales."} | {"material":true,"document":true,"quantities":true,"containerGuid":"0Wh59pm9LO_einrwiq6Es1","containerName":"Planta baja"} | {"id":"foundations","name":"Cimentaciones"} | {"profileId":"concrete_reinforced","name":"Hormigón armado · gris natural","materialName":"Hormigón armado","physicalMaterialStatus":"known","physicalMaterialSource":"EST-SB-20260710 · Estructura A201 / p. 4","appearanceStatus":"criterio_visual","appearanceBasis":"Interpretación visual del material documental; el acabado, tono y parámetros PBR no son una especificación contractual.","note":"La apariencia gráfica no modifica ni confirma la especificación física del material."} | {"elementId":"pump_house_0044","ifcGuid":"3KZfMxoNPLkPoahgAjLmNc","ifcClass":"IfcWall","buildingId":"pump_house","buildingName":"Sala de bombas contra incendios","sourceDocumentId":"EST-SB-20260710","sourceRepresentationKind":"documentary_mesh"} | {"layerId":"foundations","layerName":"Cimentaciones","role":"Muro","basis":"Clasificación por función del elemento; no modifica las especificaciones documentales."} | foundations | {"profileId":"concrete_reinforced","name":"Hormigón armado · gris natural","status":"criterio_visual","basis":"Interpretación visual del material documental; el acabado, tono y parámetros PBR no son una especificación contractual.","physicalMaterialUnchanged":true} | EST-SB-20260710 · Estructura A201 / p. 4 | Espesor de 200 mm y cotas inferior y superior según las secciones; posición en planta simplificada siguiendo el cerramiento exterior. |  |  |  | Registro de líneas del PDF general con envolvente de 10,2 × 8,2 m. Estimación de trabajo de implantación de ±0,15 m, pendiente de CAD nativo; no constituye una precisión topográfica garantizada. | Cimentación | EST-SB-20260710 · Estructura A201 / p. 4 | 286.25 | Cimentaciones | Hormigón armado · gris natural | concrete_reinforced | [0.666667,0.662745,0.619608] | 0.96 | 0 | Interpretación visual del material documental; el acabado, tono y parámetros PBR no son una especificación contractual. | Cimentación; BIM · Cimentaciones | JH_Trazabilidad - Espesor (m): 0.2; Cota inferior absoluta (m): 284.75; Cota superior absoluta (m): 286.25; Hormigón: Muro de hormigón; terminología de prefabricación y hormigonado in situ pendiente de aclaración.; JH_DimensionesDocumentadas - Espesor: 0.2 m; Cota inferior absoluta: 284.75 m; Cota superior absoluta: 286.25 m
Sala de bombas contra incendios · muro de cimentación de 200 mm · eje B | Planos de estructura de la sala de bombas contra incendios | Hormigón armado | 10.2 × 0.2 × 1.5 | 284.75 | 286.25 | 3.06 | pump_house_0045 |  | 10.1322 | 1.58742 | 1.5 | 35.28 | 3.06 | pump_house | Sala de bombas contra incendios | {"name":"Hormigón armado","source":"EST-SB-20260710 · Estructura A201 / p. 4","status":"known"} | {"documented":[{"label":"Espesor","value":0.2,"unit":"m","source":"EST-SB-20260710 · Estructura A201 / p. 4","status":"provisional"},{"label":"Cota inferior absoluta","value":284.75,"unit":"m","source":"EST-SB-20260710 · Estructura A201 / p. 4","status":"documentado"},{"label":"Cota superior absoluta","value":286.25,"unit":"m","source":"EST-SB-20260710 · Estructura A201 / p. 4","status":"documentado"}],"geometry":[{"label":"Dimensiones de la caja local del elemento (X, Y, Z)","value":"10.2 × 0.2 × 1.5","unit":"m","source":"Malla triangulada del elemento en ejes locales del edificio","status":"derivado"},{"label":"Cota mínima absoluta de la malla","value":284.75,"unit":"m","source":"Malla de proyecto y origen altimétrico 285 m","status":"derivado"},{"label":"Cota máxima absoluta de la malla","value":286.25,"unit":"m","source":"Malla de proyecto y origen altimétrico 285 m","status":"derivado"},{"label":"Volumen geométrico bruto","value":3.06,"unit":"m³","source":"Malla cerrada del elemento","status":"derivado"}],"notes":["Las dimensiones documentadas proceden de anotaciones o cuadros; la caja y el volumen se calculan a partir de la malla.","El volumen es exclusivamente geométrico y bruto; no representa una medición neta de material ni una cantidad de compra."]} | {"documentId":"EST-SB-20260710","title":"Planos de estructura de la sala de bombas contra incendios","date":"2026-07-10","sheet":"Estructura A201 / p. 4"} | ["Sistema de ejecución del muro, prefabricado o in situ, pendiente de aclaración.","Registro de líneas del PDF general con envolvente de 10,2 × 8,2 m. Estimación de trabajo de implantación de ±0,15 m, pendiente de CAD nativo; no constituye una precisión topográfica garantizada."] | {"horizontalStatus":"derivado","verticalStatus":"derivado","baseElevationM":286.25,"note":"Registro de líneas del PDF general con envolvente de 10,2 × 8,2 m. Estimación de trabajo de implantación de ±0,15 m, pendiente de CAD nativo; no constituye una precisión topográfica garantizada."} |  | {"boundingBoxM":{"min":[9.205723,33.330015,-0.25],"max":[19.337908,34.917431,1.25]},"extentsM":[10.132185,1.587416,1.5],"meshSurfaceM2":35.279996,"meshVolumeM3":3.059998,"closedSolid":true,"basis":"Geometría triangulada releída del IFC; envolventes y magnitudes no contractuales."} | {"material":true,"document":true,"quantities":true,"containerGuid":"0Wh59pm9LO_einrwiq6Es1","containerName":"Planta baja"} | {"id":"foundations","name":"Cimentaciones"} | {"profileId":"concrete_reinforced","name":"Hormigón armado · gris natural","materialName":"Hormigón armado","physicalMaterialStatus":"known","physicalMaterialSource":"EST-SB-20260710 · Estructura A201 / p. 4","appearanceStatus":"criterio_visual","appearanceBasis":"Interpretación visual del material documental; el acabado, tono y parámetros PBR no son una especificación contractual.","note":"La apariencia gráfica no modifica ni confirma la especificación física del material."} | {"elementId":"pump_house_0045","ifcGuid":"0c8WNoaynVG8kwtfod4wGa","ifcClass":"IfcWall","buildingId":"pump_house","buildingName":"Sala de bombas contra incendios","sourceDocumentId":"EST-SB-20260710","sourceRepresentationKind":"documentary_mesh"} | {"layerId":"foundations","layerName":"Cimentaciones","role":"Muro","basis":"Clasificación por función del elemento; no modifica las especificaciones documentales."} | foundations | {"profileId":"concrete_reinforced","name":"Hormigón armado · gris natural","status":"criterio_visual","basis":"Interpretación visual del material documental; el acabado, tono y parámetros PBR no son una especificación contractual.","physicalMaterialUnchanged":true} | EST-SB-20260710 · Estructura A201 / p. 4 | Espesor de 200 mm y cotas inferior y superior según las secciones; posición en planta simplificada siguiendo el cerramiento exterior. |  |  |  | Registro de líneas del PDF general con envolvente de 10,2 × 8,2 m. Estimación de trabajo de implantación de ±0,15 m, pendiente de CAD nativo; no constituye una precisión topográfica garantizada. | Cimentación | EST-SB-20260710 · Estructura A201 / p. 4 | 286.25 | Cimentaciones | Hormigón armado · gris natural | concrete_reinforced | [0.666667,0.662745,0.619608] | 0.96 | 0 | Interpretación visual del material documental; el acabado, tono y parámetros PBR no son una especificación contractual. | Cimentación; BIM · Cimentaciones | JH_Trazabilidad - Espesor (m): 0.2; Cota inferior absoluta (m): 284.75; Cota superior absoluta (m): 286.25; Hormigón: Muro de hormigón; terminología de prefabricación y hormigonado in situ pendiente de aclaración.; JH_DimensionesDocumentadas - Espesor: 0.2 m; Cota inferior absoluta: 284.75 m; Cota superior absoluta: 286.25 m
Sala de bombas contra incendios · muro de cimentación de 200 mm · eje 1 | Planos de estructura de la sala de bombas contra incendios | Hormigón armado | 0.2 × 7.8 × 1.5 | 284.75 | 286.25 | 2.34 | pump_house_0046 |  | 1.26053 | 7.75455 | 1.5 | 27.12 | 2.34 | pump_house | Sala de bombas contra incendios | {"name":"Hormigón armado","source":"EST-SB-20260710 · Estructura A201 / p. 4","status":"known"} | {"documented":[{"label":"Espesor","value":0.2,"unit":"m","source":"EST-SB-20260710 · Estructura A201 / p. 4","status":"provisional"},{"label":"Cota inferior absoluta","value":284.75,"unit":"m","source":"EST-SB-20260710 · Estructura A201 / p. 4","status":"documentado"},{"label":"Cota superior absoluta","value":286.25,"unit":"m","source":"EST-SB-20260710 · Estructura A201 / p. 4","status":"documentado"}],"geometry":[{"label":"Dimensiones de la caja local del elemento (X, Y, Z)","value":"0.2 × 7.8 × 1.5","unit":"m","source":"Malla triangulada del elemento en ejes locales del edificio","status":"derivado"},{"label":"Cota mínima absoluta de la malla","value":284.75,"unit":"m","source":"Malla de proyecto y origen altimétrico 285 m","status":"derivado"},{"label":"Cota máxima absoluta de la malla","value":286.25,"unit":"m","source":"Malla de proyecto y origen altimétrico 285 m","status":"derivado"},{"label":"Volumen geométrico bruto","value":2.34,"unit":"m³","source":"Malla cerrada del elemento","status":"derivado"}],"notes":["Las dimensiones documentadas proceden de anotaciones o cuadros; la caja y el volumen se calculan a partir de la malla.","El volumen es exclusivamente geométrico y bruto; no representa una medición neta de material ni una cantidad de compra."]} | {"documentId":"EST-SB-20260710","title":"Planos de estructura de la sala de bombas contra incendios","date":"2026-07-10","sheet":"Estructura A201 / p. 4"} | ["Sistema de ejecución del muro, prefabricado o in situ, pendiente de aclaración.","Registro de líneas del PDF general con envolvente de 10,2 × 8,2 m. Estimación de trabajo de implantación de ±0,15 m, pendiente de CAD nativo; no constituye una precisión topográfica garantizada."] | {"horizontalStatus":"derivado","verticalStatus":"derivado","baseElevationM":286.25,"note":"Registro de líneas del PDF general con envolvente de 10,2 × 8,2 m. Estimación de trabajo de implantación de ±0,15 m, pendiente de CAD nativo; no constituye una precisión topográfica garantizada."} |  | {"boundingBoxM":{"min":[8.143333,26.964744,-0.25],"max":[9.403859,34.719295,1.25]},"extentsM":[1.260526,7.754551,1.5],"meshSurfaceM2":27.119996,"meshVolumeM3":2.339998,"closedSolid":true,"basis":"Geometría triangulada releída del IFC; envolventes y magnitudes no contractuales."} | {"material":true,"document":true,"quantities":true,"containerGuid":"0Wh59pm9LO_einrwiq6Es1","containerName":"Planta baja"} | {"id":"foundations","name":"Cimentaciones"} | {"profileId":"concrete_reinforced","name":"Hormigón armado · gris natural","materialName":"Hormigón armado","physicalMaterialStatus":"known","physicalMaterialSource":"EST-SB-20260710 · Estructura A201 / p. 4","appearanceStatus":"criterio_visual","appearanceBasis":"Interpretación visual del material documental; el acabado, tono y parámetros PBR no son una especificación contractual.","note":"La apariencia gráfica no modifica ni confirma la especificación física del material."} | {"elementId":"pump_house_0046","ifcGuid":"1fSpW$3ifM3waU3gMV257v","ifcClass":"IfcWall","buildingId":"pump_house","buildingName":"Sala de bombas contra incendios","sourceDocumentId":"EST-SB-20260710","sourceRepresentationKind":"documentary_mesh"} | {"layerId":"foundations","layerName":"Cimentaciones","role":"Muro","basis":"Clasificación por función del elemento; no modifica las especificaciones documentales."} | foundations | {"profileId":"concrete_reinforced","name":"Hormigón armado · gris natural","status":"criterio_visual","basis":"Interpretación visual del material documental; el acabado, tono y parámetros PBR no son una especificación contractual.","physicalMaterialUnchanged":true} | EST-SB-20260710 · Estructura A201 / p. 4 | Espesor de 200 mm y cotas inferior y superior según las secciones; posición en planta simplificada siguiendo el cerramiento exterior. |  |  |  | Registro de líneas del PDF general con envolvente de 10,2 × 8,2 m. Estimación de trabajo de implantación de ±0,15 m, pendiente de CAD nativo; no constituye una precisión topográfica garantizada. | Cimentación | EST-SB-20260710 · Estructura A201 / p. 4 | 286.25 | Cimentaciones | Hormigón armado · gris natural | concrete_reinforced | [0.666667,0.662745,0.619608] | 0.96 | 0 | Interpretación visual del material documental; el acabado, tono y parámetros PBR no son una especificación contractual. | Cimentación; BIM · Cimentaciones | JH_Trazabilidad - Espesor (m): 0.2; Cota inferior absoluta (m): 284.75; Cota superior absoluta (m): 286.25; Hormigón: Muro de hormigón; terminología de prefabricación y hormigonado in situ pendiente de aclaración.; JH_DimensionesDocumentadas - Espesor: 0.2 m; Cota inferior absoluta: 284.75 m; Cota superior absoluta: 286.25 m
Sala de bombas contra incendios · muro de cimentación de 200 mm · eje 2 | Planos de estructura de la sala de bombas contra incendios | Hormigón armado | 0.2 × 7.8 × 1.5 | 284.75 | 286.25 | 2.34 | pump_house_0047 |  | 1.26053 | 7.75455 | 1.5 | 27.12 | 2.34 | pump_house | Sala de bombas contra incendios | {"name":"Hormigón armado","source":"EST-SB-20260710 · Estructura A201 / p. 4","status":"known"} | {"documented":[{"label":"Espesor","value":0.2,"unit":"m","source":"EST-SB-20260710 · Estructura A201 / p. 4","status":"provisional"},{"label":"Cota inferior absoluta","value":284.75,"unit":"m","source":"EST-SB-20260710 · Estructura A201 / p. 4","status":"documentado"},{"label":"Cota superior absoluta","value":286.25,"unit":"m","source":"EST-SB-20260710 · Estructura A201 / p. 4","status":"documentado"}],"geometry":[{"label":"Dimensiones de la caja local del elemento (X, Y, Z)","value":"0.2 × 7.8 × 1.5","unit":"m","source":"Malla triangulada del elemento en ejes locales del edificio","status":"derivado"},{"label":"Cota mínima absoluta de la malla","value":284.75,"unit":"m","source":"Malla de proyecto y origen altimétrico 285 m","status":"derivado"},{"label":"Cota máxima absoluta de la malla","value":286.25,"unit":"m","source":"Malla de proyecto y origen altimétrico 285 m","status":"derivado"},{"label":"Volumen geométrico bruto","value":2.34,"unit":"m³","source":"Malla cerrada del elemento","status":"derivado"}],"notes":["Las dimensiones documentadas proceden de anotaciones o cuadros; la caja y el volumen se calculan a partir de la malla.","El volumen es exclusivamente geométrico y bruto; no representa una medición neta de material ni una cantidad de compra."]} | {"documentId":"EST-SB-20260710","title":"Planos de estructura de la sala de bombas contra incendios","date":"2026-07-10","sheet":"Estructura A201 / p. 4"} | ["Sistema de ejecución del muro, prefabricado o in situ, pendiente de aclaración.","Registro de líneas del PDF general con envolvente de 10,2 × 8,2 m. Estimación de trabajo de implantación de ±0,15 m, pendiente de CAD nativo; no constituye una precisión topográfica garantizada."] | {"horizontalStatus":"derivado","verticalStatus":"derivado","baseElevationM":286.25,"note":"Registro de líneas del PDF general con envolvente de 10,2 × 8,2 m. Estimación de trabajo de implantación de ±0,15 m, pendiente de CAD nativo; no constituye una precisión topográfica garantizada."} |  | {"boundingBoxM":{"min":[18.050141,25.602705,-0.25],"max":[19.310667,33.357256,1.25]},"extentsM":[1.260526,7.754551,1.5],"meshSurfaceM2":27.119996,"meshVolumeM3":2.339998,"closedSolid":true,"basis":"Geometría triangulada releída del IFC; envolventes y magnitudes no contractuales."} | {"material":true,"document":true,"quantities":true,"containerGuid":"0Wh59pm9LO_einrwiq6Es1","containerName":"Planta baja"} | {"id":"foundations","name":"Cimentaciones"} | {"profileId":"concrete_reinforced","name":"Hormigón armado · gris natural","materialName":"Hormigón armado","physicalMaterialStatus":"known","physicalMaterialSource":"EST-SB-20260710 · Estructura A201 / p. 4","appearanceStatus":"criterio_visual","appearanceBasis":"Interpretación visual del material documental; el acabado, tono y parámetros PBR no son una especificación contractual.","note":"La apariencia gráfica no modifica ni confirma la especificación física del material."} | {"elementId":"pump_house_0047","ifcGuid":"1qJwvOZaPLTv7RgGE03xSH","ifcClass":"IfcWall","buildingId":"pump_house","buildingName":"Sala de bombas contra incendios","sourceDocumentId":"EST-SB-20260710","sourceRepresentationKind":"documentary_mesh"} | {"layerId":"foundations","layerName":"Cimentaciones","role":"Muro","basis":"Clasificación por función del elemento; no modifica las especificaciones documentales."} | foundations | {"profileId":"concrete_reinforced","name":"Hormigón armado · gris natural","status":"criterio_visual","basis":"Interpretación visual del material documental; el acabado, tono y parámetros PBR no son una especificación contractual.","physicalMaterialUnchanged":true} | EST-SB-20260710 · Estructura A201 / p. 4 | Espesor de 200 mm y cotas inferior y superior según las secciones; posición en planta simplificada siguiendo el cerramiento exterior. |  |  |  | Registro de líneas del PDF general con envolvente de 10,2 × 8,2 m. Estimación de trabajo de implantación de ±0,15 m, pendiente de CAD nativo; no constituye una precisión topográfica garantizada. | Cimentación | EST-SB-20260710 · Estructura A201 / p. 4 | 286.25 | Cimentaciones | Hormigón armado · gris natural | concrete_reinforced | [0.666667,0.662745,0.619608] | 0.96 | 0 | Interpretación visual del material documental; el acabado, tono y parámetros PBR no son una especificación contractual. | Cimentación; BIM · Cimentaciones | JH_Trazabilidad - Espesor (m): 0.2; Cota inferior absoluta (m): 284.75; Cota superior absoluta (m): 286.25; Hormigón: Muro de hormigón; terminología de prefabricación y hormigonado in situ pendiente de aclaración.; JH_DimensionesDocumentadas - Espesor: 0.2 m; Cota inferior absoluta: 284.75 m; Cota superior absoluta: 286.25 m
Edificio de oficinas · Fábrica de bloques huecos de hormigón de 200 mm · eje A · tramo 01 | Planos de arquitectura del edificio de oficinas | Bloque hueco de hormigón de árido ligero | 1 × 0.2 × 1.1 | 285.95 | 287.05 | 0.22 | office_0065 | yes | 0.33434 | 1.01792 | 1.1 | 3.04 | 0.22 | office | Edificio de oficinas | {"name":"Bloque hueco de hormigón de árido ligero","source":"ARQ-OF-20260710 · Arquitectura A101 / p. 3, A103 / p. 5, A106 / p. 8; A301Cuadro de materiales ","status":"known"} | {"documented":[{"label":"Espesor del muro","value":0.2,"unit":"m","source":"ARQ-OF-20260710 · Arquitectura A101 / p. 3, A103 / p. 5, A106 / p. 8; A301Cuadro de materiales ","status":"documentado"}],"geometry":[{"label":"Dimensiones de la caja local del elemento (X, Y, Z)","value":"1 × 0.2 × 1.1","unit":"m","source":"Malla triangulada del elemento en ejes locales del edificio","status":"derivado"},{"label":"Cota mínima absoluta de la malla","value":285.95,"unit":"m","source":"Malla de proyecto y origen altimétrico 285 m","status":"derivado"},{"label":"Cota máxima absoluta de la malla","value":287.05,"unit":"m","source":"Malla de proyecto y origen altimétrico 285 m","status":"derivado"},{"label":"Volumen geométrico bruto","value":0.22,"unit":"m³","source":"Malla cerrada del elemento","status":"derivado"}],"notes":["Las dimensiones documentadas proceden de anotaciones o cuadros; la caja y el volumen se calculan a partir de la malla.","El volumen es exclusivamente geométrico y bruto; no representa una medición neta de material ni una cantidad de compra."]} | {"documentId":"ARQ-OF-20260710","title":"Planos de arquitectura del edificio de oficinas","date":"2026-07-10","sheet":"Arquitectura A101 / p. 3, A103 / p. 5, A106 / p. 8; A301Cuadro de materiales "} | ["El plano general de 2026-07-31 mantiene el edificio de oficinas de 200 m², mientras documentación anterior indica su supresión. Se conserva lo dibujado, pendiente de confirmación de la propiedad y del equipo de diseño.","Envolvente exterior controlada por la planta de arquitectura; no se han modelado individualmente todas las capas de acabado.","Registro de líneas del PDF general, envolvente de 20 × 10 m; eje local 1 al norte y acceso del lado A al oeste. Estimación de trabajo de implantación de ±0,15 m, pendiente de CAD; no constituye una precisión topográfica garantizada."] | {"horizontalStatus":"derivado","verticalStatus":"derivado","baseElevationM":285.95,"note":"Registro de líneas del PDF general, envolvente de 20 × 10 m; eje local 1 al norte y acceso del lado A al oeste. Estimación de trabajo de implantación de ±0,15 m, pendiente de CAD; no constituye una precisión topográfica garantizada."} | {"Pset_WallCommon":{"IsExternal":{"value":true,"source":"ARQ-OF-20260710 · A101, A103 y alzados; elemento de la envolvente exterior identificada en planta","status":"known"}}} | {"boundingBoxM":{"min":[17.406431,91.899906,0.95],"max":[17.740771,92.917828,2.05]},"extentsM":[0.33434,1.017922,1.1],"meshSurfaceM2":3.04,"meshVolumeM3":0.22,"closedSolid":true,"basis":"Geometría triangulada releída del IFC; envolventes y magnitudes no contractuales."} | {"material":true,"document":true,"quantities":true,"containerGuid":"3ztlotcerHPueDgxP84R6z","containerName":"Planta baja"} | {"id":"architecture","name":"Arquitectura"} | {"profileId":"block_masonry","name":"Fábrica de bloques · acabado mineral claro","materialName":"Bloque hueco de hormigón de árido ligero","physicalMaterialStatus":"known","physicalMaterialSource":"ARQ-OF-20260710 · Arquitectura A101 / p. 3, A103 / p. 5, A106 / p. 8; A301Cuadro de materiales ","appearanceStatus":"criterio_visual","appearanceBasis":"Bloque hueco documentado. Apariencia mineral clara para distinguir el cerramiento; no confirma un revoco ni su espesor.","note":"La apariencia gráfica no modifica ni confirma la especificación física del material."} | {"elementId":"office_0065","ifcGuid":"0iKzWXCBXSlvxuqsmRNxoj","ifcClass":"IfcWall","buildingId":"office","buildingName":"Edificio de oficinas","sourceDocumentId":"ARQ-OF-20260710","sourceRepresentationKind":"documentary_mesh"} | {"layerId":"architecture","layerName":"Arquitectura","role":"Muro","basis":"Clasificación por función del elemento; no modifica las especificaciones documentales."} | architecture | {"profileId":"block_masonry","name":"Fábrica de bloques · acabado mineral claro","status":"criterio_visual","basis":"Bloque hueco documentado. Apariencia mineral clara para distinguir el cerramiento; no confirma un revoco ni su espesor.","physicalMaterialUnchanged":true} | ARQ-OF-20260710 · Arquitectura A101 / p. 3, A103 / p. 5, A106 / p. 8; A301Cuadro de materiales | Dimensiones contrastadas con los planos; reconstrucción geométrica a partir de documentación de diseño. | 0.2 | Muros segmentados con huecos reales para puertas y ventanas. | Envolvente exterior controlada por la planta de arquitectura; no se han modelado individualmente todas las capas de acabado. | Registro de líneas del PDF general, envolvente de 20 × 10 m; eje local 1 al norte y acceso del lado A al oeste. Estimación de trabajo de implantación de ±0,15 m, pendiente de CAD; no constituye una precisión topográfica garantizada. | Arquitectura | ARQ-OF-20260710 · Arquitectura A101 / p. 3, A103 / p. 5, A106 / p. 8; A301Cuadro de materiales | 285.95 | Arquitectura | Fábrica de bloques · acabado mineral claro | block_masonry | [0.843137,0.823529,0.772549] | 0.96 | 0 | Bloque hueco documentado. Apariencia mineral clara para distinguir el cerramiento; no confirma un revoco ni su espesor. | Arquitectura; BIM · Arquitectura | El plano general de 2026-07-31 mantiene el edificio de oficinas de 200 m², mientras documentación anterior indica su supresión. Se conserva lo dibujado, pendiente de confirmación de la propiedad y del equipo de diseño.
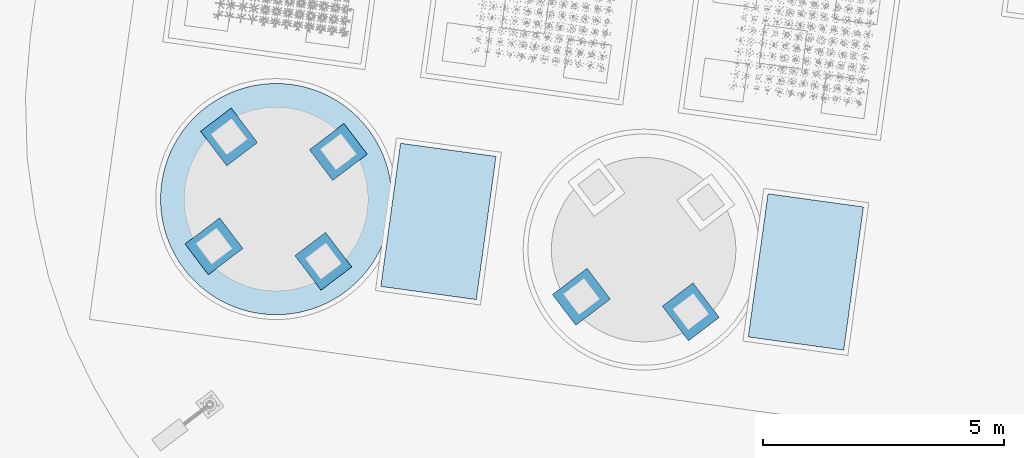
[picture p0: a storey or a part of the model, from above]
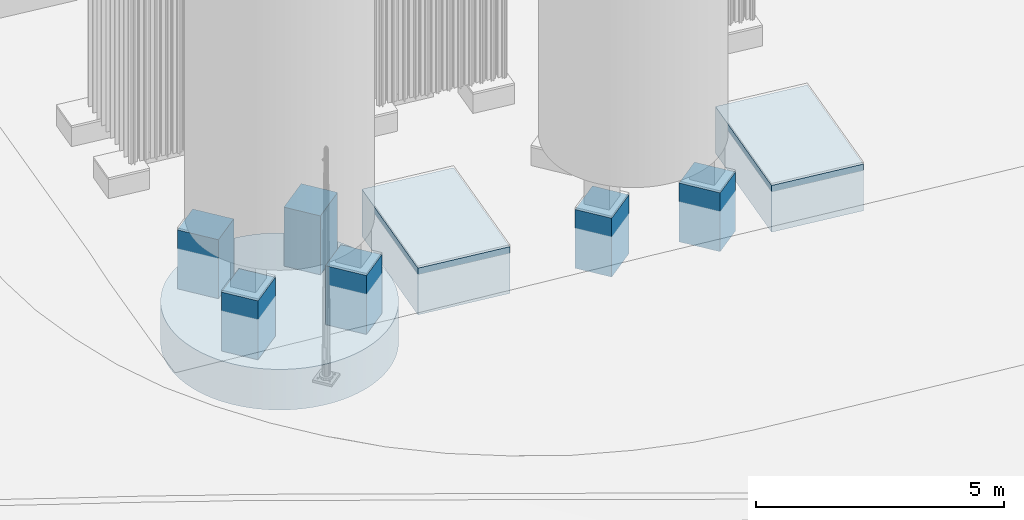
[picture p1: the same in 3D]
Properties of the parts of a building model (IFC4), part 117 of 134

# IfcWall (187)
Name | Document | Material = JH_Trazabilidad, Material = name | Dimensiones de la caja local del elemento (X, Y, Z) | Cota mínima absoluta de la malla (m) | Cota máxima absoluta de la malla (m) | Volumen geométrico bruto (m3) = Volumen geométrico (m³) | Reference = Identificador del elemento = Identificador | IsExternal | ExtensionX (m) | ExtensionY (m) | ExtensionZ (m) | SuperficieDeLaMalla (m2) | VolumenGeometrico (m3) = GrossVolume (m3) | buildingId | buildingName = Edificio | material | dimensions | JH_InformacionBIM, source = DocumentoFuente | issues = IncidenciasPendientes | positioning = PosicionYEstado | commonProperties | geometryMetrics | ifcAssociations | visualLayer | materialAppearance | visualizationIdentity | classification | layerId = IdentificadorCapa | appearance | Planos de referencia | Base geométrica | Espesor del muro (m) = Espesor del muro (m) | Tratamiento de los huecos | Representación de los acabados | Estado de la implantación | Disciplina | Referencia del material = JH_EvidenciaDeMaterial, source | Cota de planta baja terminada (m) | Capa BIM = NombreCapa | Acabado de visualización = Acabado | Perfil | ColorRGB | Rugosidad | Metallicidad | Referencia | Group | Discrepancia entre versiones
Edificio de oficinas · Fábrica de bloques huecos de hormigón de 200 mm · eje A · tramo 02 | Planos de arquitectura del edificio de oficinas | Bloque hueco de hormigón de árido ligero | 1 × 0.2 × 1.2 | 287.05 | 288.25 | 0.24 | office_0066 | yes | 0.33434 | 1.01792 | 1.2 | 3.28 | 0.24 | office | Edificio de oficinas | {"name":"Bloque hueco de hormigón de árido ligero","source":"ARQ-OF-20260710 · Arquitectura A101 / p. 3, A103 / p. 5, A106 / p. 8; A301Cuadro de materiales ","status":"known"} | {"documented":[{"label":"Espesor del muro","value":0.2,"unit":"m","source":"ARQ-OF-20260710 · Arquitectura A101 / p. 3, A103 / p. 5, A106 / p. 8; A301Cuadro de materiales ","status":"documentado"}],"geometry":[{"label":"Dimensiones de la caja local del elemento (X, Y, Z)","value":"1 × 0.2 × 1.2","unit":"m","source":"Malla triangulada del elemento en ejes locales del edificio","status":"derivado"},{"label":"Cota mínima absoluta de la malla","value":287.05,"unit":"m","source":"Malla de proyecto y origen altimétrico 285 m","status":"derivado"},{"label":"Cota máxima absoluta de la malla","value":288.25,"unit":"m","source":"Malla de proyecto y origen altimétrico 285 m","status":"derivado"},{"label":"Volumen geométrico bruto","value":0.24,"unit":"m³","source":"Malla cerrada del elemento","status":"derivado"}],"notes":["Las dimensiones documentadas proceden de anotaciones o cuadros; la caja y el volumen se calculan a partir de la malla.","El volumen es exclusivamente geométrico y bruto; no representa una medición neta de material ni una cantidad de compra."]} | {"documentId":"ARQ-OF-20260710","title":"Planos de arquitectura del edificio de oficinas","date":"2026-07-10","sheet":"Arquitectura A101 / p. 3, A103 / p. 5, A106 / p. 8; A301Cuadro de materiales "} | ["El plano general de 2026-07-31 mantiene el edificio de oficinas de 200 m², mientras documentación anterior indica su supresión. Se conserva lo dibujado, pendiente de confirmación de la propiedad y del equipo de diseño.","Envolvente exterior controlada por la planta de arquitectura; no se han modelado individualmente todas las capas de acabado.","Registro de líneas del PDF general, envolvente de 20 × 10 m; eje local 1 al norte y acceso del lado A al oeste. Estimación de trabajo de implantación de ±0,15 m, pendiente de CAD; no constituye una precisión topográfica garantizada."] | {"horizontalStatus":"derivado","verticalStatus":"derivado","baseElevationM":285.95,"note":"Registro de líneas del PDF general, envolvente de 20 × 10 m; eje local 1 al norte y acceso del lado A al oeste. Estimación de trabajo de implantación de ±0,15 m, pendiente de CAD; no constituye una precisión topográfica garantizada."} | {"Pset_WallCommon":{"IsExternal":{"value":true,"source":"ARQ-OF-20260710 · A101, A103 y alzados; elemento de la envolvente exterior identificada en planta","status":"known"}}} | {"boundingBoxM":{"min":[17.406431,91.899906,2.05],"max":[17.740771,92.917828,3.25]},"extentsM":[0.33434,1.017922,1.2],"meshSurfaceM2":3.28,"meshVolumeM3":0.24,"closedSolid":true,"basis":"Geometría triangulada releída del IFC; envolventes y magnitudes no contractuales."} | {"material":true,"document":true,"quantities":true,"containerGuid":"3ztlotcerHPueDgxP84R6z","containerName":"Planta baja"} | {"id":"architecture","name":"Arquitectura"} | {"profileId":"block_masonry","name":"Fábrica de bloques · acabado mineral claro","materialName":"Bloque hueco de hormigón de árido ligero","physicalMaterialStatus":"known","physicalMaterialSource":"ARQ-OF-20260710 · Arquitectura A101 / p. 3, A103 / p. 5, A106 / p. 8; A301Cuadro de materiales ","appearanceStatus":"criterio_visual","appearanceBasis":"Bloque hueco documentado. Apariencia mineral clara para distinguir el cerramiento; no confirma un revoco ni su espesor.","note":"La apariencia gráfica no modifica ni confirma la especificación física del material."} | {"elementId":"office_0066","ifcGuid":"14nAdpEZDV3P5H0UdSw1cq","ifcClass":"IfcWall","buildingId":"office","buildingName":"Edificio de oficinas","sourceDocumentId":"ARQ-OF-20260710","sourceRepresentationKind":"documentary_mesh"} | {"layerId":"architecture","layerName":"Arquitectura","role":"Muro","basis":"Clasificación por función del elemento; no modifica las especificaciones documentales."} | architecture | {"profileId":"block_masonry","name":"Fábrica de bloques · acabado mineral claro","status":"criterio_visual","basis":"Bloque hueco documentado. Apariencia mineral clara para distinguir el cerramiento; no confirma un revoco ni su espesor.","physicalMaterialUnchanged":true} | ARQ-OF-20260710 · Arquitectura A101 / p. 3, A103 / p. 5, A106 / p. 8; A301Cuadro de materiales | Dimensiones contrastadas con los planos; reconstrucción geométrica a partir de documentación de diseño. | 0.2 | Muros segmentados con huecos reales para puertas y ventanas. | Envolvente exterior controlada por la planta de arquitectura; no se han modelado individualmente todas las capas de acabado. | Registro de líneas del PDF general, envolvente de 20 × 10 m; eje local 1 al norte y acceso del lado A al oeste. Estimación de trabajo de implantación de ±0,15 m, pendiente de CAD; no constituye una precisión topográfica garantizada. | Arquitectura | ARQ-OF-20260710 · Arquitectura A101 / p. 3, A103 / p. 5, A106 / p. 8; A301Cuadro de materiales | 285.95 | Arquitectura | Fábrica de bloques · acabado mineral claro | block_masonry | [0.843137,0.823529,0.772549] | 0.96 | 0 | Bloque hueco documentado. Apariencia mineral clara para distinguir el cerramiento; no confirma un revoco ni su espesor. | Arquitectura; BIM · Arquitectura | El plano general de 2026-07-31 mantiene el edificio de oficinas de 200 m², mientras documentación anterior indica su supresión. Se conserva lo dibujado, pendiente de confirmación de la propiedad y del equipo de diseño.
Edificio de oficinas · Fábrica de bloques huecos de hormigón de 200 mm · eje A · tramo 03 | Planos de arquitectura del edificio de oficinas | Bloque hueco de hormigón de árido ligero | 1 × 0.2 × 1.1 | 288.25 | 289.35 | 0.22 | office_0067 | yes | 0.33434 | 1.01792 | 1.1 | 3.04 | 0.22 | office | Edificio de oficinas | {"name":"Bloque hueco de hormigón de árido ligero","source":"ARQ-OF-20260710 · Arquitectura A101 / p. 3, A103 / p. 5, A106 / p. 8; A301Cuadro de materiales ","status":"known"} | {"documented":[{"label":"Espesor del muro","value":0.2,"unit":"m","source":"ARQ-OF-20260710 · Arquitectura A101 / p. 3, A103 / p. 5, A106 / p. 8; A301Cuadro de materiales ","status":"documentado"}],"geometry":[{"label":"Dimensiones de la caja local del elemento (X, Y, Z)","value":"1 × 0.2 × 1.1","unit":"m","source":"Malla triangulada del elemento en ejes locales del edificio","status":"derivado"},{"label":"Cota mínima absoluta de la malla","value":288.25,"unit":"m","source":"Malla de proyecto y origen altimétrico 285 m","status":"derivado"},{"label":"Cota máxima absoluta de la malla","value":289.35,"unit":"m","source":"Malla de proyecto y origen altimétrico 285 m","status":"derivado"},{"label":"Volumen geométrico bruto","value":0.22,"unit":"m³","source":"Malla cerrada del elemento","status":"derivado"}],"notes":["Las dimensiones documentadas proceden de anotaciones o cuadros; la caja y el volumen se calculan a partir de la malla.","El volumen es exclusivamente geométrico y bruto; no representa una medición neta de material ni una cantidad de compra."]} | {"documentId":"ARQ-OF-20260710","title":"Planos de arquitectura del edificio de oficinas","date":"2026-07-10","sheet":"Arquitectura A101 / p. 3, A103 / p. 5, A106 / p. 8; A301Cuadro de materiales "} | ["El plano general de 2026-07-31 mantiene el edificio de oficinas de 200 m², mientras documentación anterior indica su supresión. Se conserva lo dibujado, pendiente de confirmación de la propiedad y del equipo de diseño.","Envolvente exterior controlada por la planta de arquitectura; no se han modelado individualmente todas las capas de acabado.","Registro de líneas del PDF general, envolvente de 20 × 10 m; eje local 1 al norte y acceso del lado A al oeste. Estimación de trabajo de implantación de ±0,15 m, pendiente de CAD; no constituye una precisión topográfica garantizada."] | {"horizontalStatus":"derivado","verticalStatus":"derivado","baseElevationM":285.95,"note":"Registro de líneas del PDF general, envolvente de 20 × 10 m; eje local 1 al norte y acceso del lado A al oeste. Estimación de trabajo de implantación de ±0,15 m, pendiente de CAD; no constituye una precisión topográfica garantizada."} | {"Pset_WallCommon":{"IsExternal":{"value":true,"source":"ARQ-OF-20260710 · A101, A103 y alzados; elemento de la envolvente exterior identificada en planta","status":"known"}}} | {"boundingBoxM":{"min":[17.406431,91.899906,3.25],"max":[17.740771,92.917828,4.35]},"extentsM":[0.33434,1.017922,1.1],"meshSurfaceM2":3.04,"meshVolumeM3":0.22,"closedSolid":true,"basis":"Geometría triangulada releída del IFC; envolventes y magnitudes no contractuales."} | {"material":true,"document":true,"quantities":true,"containerGuid":"3ztlotcerHPueDgxP84R6z","containerName":"Planta baja"} | {"id":"architecture","name":"Arquitectura"} | {"profileId":"block_masonry","name":"Fábrica de bloques · acabado mineral claro","materialName":"Bloque hueco de hormigón de árido ligero","physicalMaterialStatus":"known","physicalMaterialSource":"ARQ-OF-20260710 · Arquitectura A101 / p. 3, A103 / p. 5, A106 / p. 8; A301Cuadro de materiales ","appearanceStatus":"criterio_visual","appearanceBasis":"Bloque hueco documentado. Apariencia mineral clara para distinguir el cerramiento; no confirma un revoco ni su espesor.","note":"La apariencia gráfica no modifica ni confirma la especificación física del material."} | {"elementId":"office_0067","ifcGuid":"2TTR2H6DTKpx$3wJ9VKBOw","ifcClass":"IfcWall","buildingId":"office","buildingName":"Edificio de oficinas","sourceDocumentId":"ARQ-OF-20260710","sourceRepresentationKind":"documentary_mesh"} | {"layerId":"architecture","layerName":"Arquitectura","role":"Muro","basis":"Clasificación por función del elemento; no modifica las especificaciones documentales."} | architecture | {"profileId":"block_masonry","name":"Fábrica de bloques · acabado mineral claro","status":"criterio_visual","basis":"Bloque hueco documentado. Apariencia mineral clara para distinguir el cerramiento; no confirma un revoco ni su espesor.","physicalMaterialUnchanged":true} | ARQ-OF-20260710 · Arquitectura A101 / p. 3, A103 / p. 5, A106 / p. 8; A301Cuadro de materiales | Dimensiones contrastadas con los planos; reconstrucción geométrica a partir de documentación de diseño. | 0.2 | Muros segmentados con huecos reales para puertas y ventanas. | Envolvente exterior controlada por la planta de arquitectura; no se han modelado individualmente todas las capas de acabado. | Registro de líneas del PDF general, envolvente de 20 × 10 m; eje local 1 al norte y acceso del lado A al oeste. Estimación de trabajo de implantación de ±0,15 m, pendiente de CAD; no constituye una precisión topográfica garantizada. | Arquitectura | ARQ-OF-20260710 · Arquitectura A101 / p. 3, A103 / p. 5, A106 / p. 8; A301Cuadro de materiales | 285.95 | Arquitectura | Fábrica de bloques · acabado mineral claro | block_masonry | [0.843137,0.823529,0.772549] | 0.96 | 0 | Bloque hueco documentado. Apariencia mineral clara para distinguir el cerramiento; no confirma un revoco ni su espesor. | Arquitectura; BIM · Arquitectura | El plano general de 2026-07-31 mantiene el edificio de oficinas de 200 m², mientras documentación anterior indica su supresión. Se conserva lo dibujado, pendiente de confirmación de la propiedad y del equipo de diseño.
Edificio de oficinas · Fábrica de bloques huecos de hormigón de 200 mm · eje A · tramo 04 | Planos de arquitectura del edificio de oficinas | Bloque hueco de hormigón de árido ligero | 1 × 0.2 × 1.6 | 289.35 | 290.95 | 0.32 | office_0068 | yes | 0.33434 | 1.01792 | 1.6 | 4.24 | 0.32 | office | Edificio de oficinas | {"name":"Bloque hueco de hormigón de árido ligero","source":"ARQ-OF-20260710 · Arquitectura A101 / p. 3, A103 / p. 5, A106 / p. 8; A301Cuadro de materiales ","status":"known"} | {"documented":[{"label":"Espesor del muro","value":0.2,"unit":"m","source":"ARQ-OF-20260710 · Arquitectura A101 / p. 3, A103 / p. 5, A106 / p. 8; A301Cuadro de materiales ","status":"documentado"}],"geometry":[{"label":"Dimensiones de la caja local del elemento (X, Y, Z)","value":"1 × 0.2 × 1.6","unit":"m","source":"Malla triangulada del elemento en ejes locales del edificio","status":"derivado"},{"label":"Cota mínima absoluta de la malla","value":289.35,"unit":"m","source":"Malla de proyecto y origen altimétrico 285 m","status":"derivado"},{"label":"Cota máxima absoluta de la malla","value":290.95,"unit":"m","source":"Malla de proyecto y origen altimétrico 285 m","status":"derivado"},{"label":"Volumen geométrico bruto","value":0.32,"unit":"m³","source":"Malla cerrada del elemento","status":"derivado"}],"notes":["Las dimensiones documentadas proceden de anotaciones o cuadros; la caja y el volumen se calculan a partir de la malla.","El volumen es exclusivamente geométrico y bruto; no representa una medición neta de material ni una cantidad de compra."]} | {"documentId":"ARQ-OF-20260710","title":"Planos de arquitectura del edificio de oficinas","date":"2026-07-10","sheet":"Arquitectura A101 / p. 3, A103 / p. 5, A106 / p. 8; A301Cuadro de materiales "} | ["El plano general de 2026-07-31 mantiene el edificio de oficinas de 200 m², mientras documentación anterior indica su supresión. Se conserva lo dibujado, pendiente de confirmación de la propiedad y del equipo de diseño.","Envolvente exterior controlada por la planta de arquitectura; no se han modelado individualmente todas las capas de acabado.","Registro de líneas del PDF general, envolvente de 20 × 10 m; eje local 1 al norte y acceso del lado A al oeste. Estimación de trabajo de implantación de ±0,15 m, pendiente de CAD; no constituye una precisión topográfica garantizada."] | {"horizontalStatus":"derivado","verticalStatus":"derivado","baseElevationM":285.95,"note":"Registro de líneas del PDF general, envolvente de 20 × 10 m; eje local 1 al norte y acceso del lado A al oeste. Estimación de trabajo de implantación de ±0,15 m, pendiente de CAD; no constituye una precisión topográfica garantizada."} | {"Pset_WallCommon":{"IsExternal":{"value":true,"source":"ARQ-OF-20260710 · A101, A103 y alzados; elemento de la envolvente exterior identificada en planta","status":"known"}}} | {"boundingBoxM":{"min":[17.406431,91.899906,4.35],"max":[17.740771,92.917828,5.95]},"extentsM":[0.33434,1.017922,1.6],"meshSurfaceM2":4.24,"meshVolumeM3":0.32,"closedSolid":true,"basis":"Geometría triangulada releída del IFC; envolventes y magnitudes no contractuales."} | {"material":true,"document":true,"quantities":true,"containerGuid":"3ztlotcerHPueDgxP84R6z","containerName":"Planta baja"} | {"id":"architecture","name":"Arquitectura"} | {"profileId":"block_masonry","name":"Fábrica de bloques · acabado mineral claro","materialName":"Bloque hueco de hormigón de árido ligero","physicalMaterialStatus":"known","physicalMaterialSource":"ARQ-OF-20260710 · Arquitectura A101 / p. 3, A103 / p. 5, A106 / p. 8; A301Cuadro de materiales ","appearanceStatus":"criterio_visual","appearanceBasis":"Bloque hueco documentado. Apariencia mineral clara para distinguir el cerramiento; no confirma un revoco ni su espesor.","note":"La apariencia gráfica no modifica ni confirma la especificación física del material."} | {"elementId":"office_0068","ifcGuid":"212nep0i1K7xZ$OsPDFg2p","ifcClass":"IfcWall","buildingId":"office","buildingName":"Edificio de oficinas","sourceDocumentId":"ARQ-OF-20260710","sourceRepresentationKind":"documentary_mesh"} | {"layerId":"architecture","layerName":"Arquitectura","role":"Muro","basis":"Clasificación por función del elemento; no modifica las especificaciones documentales."} | architecture | {"profileId":"block_masonry","name":"Fábrica de bloques · acabado mineral claro","status":"criterio_visual","basis":"Bloque hueco documentado. Apariencia mineral clara para distinguir el cerramiento; no confirma un revoco ni su espesor.","physicalMaterialUnchanged":true} | ARQ-OF-20260710 · Arquitectura A101 / p. 3, A103 / p. 5, A106 / p. 8; A301Cuadro de materiales | Dimensiones contrastadas con los planos; reconstrucción geométrica a partir de documentación de diseño. | 0.2 | Muros segmentados con huecos reales para puertas y ventanas. | Envolvente exterior controlada por la planta de arquitectura; no se han modelado individualmente todas las capas de acabado. | Registro de líneas del PDF general, envolvente de 20 × 10 m; eje local 1 al norte y acceso del lado A al oeste. Estimación de trabajo de implantación de ±0,15 m, pendiente de CAD; no constituye una precisión topográfica garantizada. | Arquitectura | ARQ-OF-20260710 · Arquitectura A101 / p. 3, A103 / p. 5, A106 / p. 8; A301Cuadro de materiales | 285.95 | Arquitectura | Fábrica de bloques · acabado mineral claro | block_masonry | [0.843137,0.823529,0.772549] | 0.96 | 0 | Bloque hueco documentado. Apariencia mineral clara para distinguir el cerramiento; no confirma un revoco ni su espesor. | Arquitectura; BIM · Arquitectura | El plano general de 2026-07-31 mantiene el edificio de oficinas de 200 m², mientras documentación anterior indica su supresión. Se conserva lo dibujado, pendiente de confirmación de la propiedad y del equipo de diseño.
Edificio de oficinas · Fábrica de bloques huecos de hormigón de 200 mm · eje A · tramo 05 | Planos de arquitectura del edificio de oficinas | Bloque hueco de hormigón de árido ligero | 1.5 × 0.2 × 1.1 | 288.25 | 289.35 | 0.33 | office_0069 | yes | 0.402442 | 1.51326 | 1.1 | 4.34 | 0.33 | office | Edificio de oficinas | {"name":"Bloque hueco de hormigón de árido ligero","source":"ARQ-OF-20260710 · Arquitectura A101 / p. 3, A103 / p. 5, A106 / p. 8; A301Cuadro de materiales ","status":"known"} | {"documented":[{"label":"Espesor del muro","value":0.2,"unit":"m","source":"ARQ-OF-20260710 · Arquitectura A101 / p. 3, A103 / p. 5, A106 / p. 8; A301Cuadro de materiales ","status":"documentado"}],"geometry":[{"label":"Dimensiones de la caja local del elemento (X, Y, Z)","value":"1.5 × 0.2 × 1.1","unit":"m","source":"Malla triangulada del elemento en ejes locales del edificio","status":"derivado"},{"label":"Cota mínima absoluta de la malla","value":288.25,"unit":"m","source":"Malla de proyecto y origen altimétrico 285 m","status":"derivado"},{"label":"Cota máxima absoluta de la malla","value":289.35,"unit":"m","source":"Malla de proyecto y origen altimétrico 285 m","status":"derivado"},{"label":"Volumen geométrico bruto","value":0.33,"unit":"m³","source":"Malla cerrada del elemento","status":"derivado"}],"notes":["Las dimensiones documentadas proceden de anotaciones o cuadros; la caja y el volumen se calculan a partir de la malla.","El volumen es exclusivamente geométrico y bruto; no representa una medición neta de material ni una cantidad de compra."]} | {"documentId":"ARQ-OF-20260710","title":"Planos de arquitectura del edificio de oficinas","date":"2026-07-10","sheet":"Arquitectura A101 / p. 3, A103 / p. 5, A106 / p. 8; A301Cuadro de materiales "} | ["El plano general de 2026-07-31 mantiene el edificio de oficinas de 200 m², mientras documentación anterior indica su supresión. Se conserva lo dibujado, pendiente de confirmación de la propiedad y del equipo de diseño.","Envolvente exterior controlada por la planta de arquitectura; no se han modelado individualmente todas las capas de acabado.","Registro de líneas del PDF general, envolvente de 20 × 10 m; eje local 1 al norte y acceso del lado A al oeste. Estimación de trabajo de implantación de ±0,15 m, pendiente de CAD; no constituye una precisión topográfica garantizada."] | {"horizontalStatus":"derivado","verticalStatus":"derivado","baseElevationM":285.95,"note":"Registro de líneas del PDF general, envolvente de 20 × 10 m; eje local 1 al norte y acceso del lado A al oeste. Estimación de trabajo de implantación de ±0,15 m, pendiente de CAD; no constituye una precisión topográfica garantizada."} | {"Pset_WallCommon":{"IsExternal":{"value":true,"source":"ARQ-OF-20260710 · A101, A103 y alzados; elemento de la envolvente exterior identificada en planta","status":"known"}}} | {"boundingBoxM":{"min":[17.202125,90.413885,3.25],"max":[17.604567,91.927147,4.35]},"extentsM":[0.402442,1.513262,1.1],"meshSurfaceM2":4.339999,"meshVolumeM3":0.33,"closedSolid":true,"basis":"Geometría triangulada releída del IFC; envolventes y magnitudes no contractuales."} | {"material":true,"document":true,"quantities":true,"containerGuid":"3ztlotcerHPueDgxP84R6z","containerName":"Planta baja"} | {"id":"architecture","name":"Arquitectura"} | {"profileId":"block_masonry","name":"Fábrica de bloques · acabado mineral claro","materialName":"Bloque hueco de hormigón de árido ligero","physicalMaterialStatus":"known","physicalMaterialSource":"ARQ-OF-20260710 · Arquitectura A101 / p. 3, A103 / p. 5, A106 / p. 8; A301Cuadro de materiales ","appearanceStatus":"criterio_visual","appearanceBasis":"Bloque hueco documentado. Apariencia mineral clara para distinguir el cerramiento; no confirma un revoco ni su espesor.","note":"La apariencia gráfica no modifica ni confirma la especificación física del material."} | {"elementId":"office_0069","ifcGuid":"1GS_lA_VrThAmWeNRHj4KD","ifcClass":"IfcWall","buildingId":"office","buildingName":"Edificio de oficinas","sourceDocumentId":"ARQ-OF-20260710","sourceRepresentationKind":"documentary_mesh"} | {"layerId":"architecture","layerName":"Arquitectura","role":"Muro","basis":"Clasificación por función del elemento; no modifica las especificaciones documentales."} | architecture | {"profileId":"block_masonry","name":"Fábrica de bloques · acabado mineral claro","status":"criterio_visual","basis":"Bloque hueco documentado. Apariencia mineral clara para distinguir el cerramiento; no confirma un revoco ni su espesor.","physicalMaterialUnchanged":true} | ARQ-OF-20260710 · Arquitectura A101 / p. 3, A103 / p. 5, A106 / p. 8; A301Cuadro de materiales | Dimensiones contrastadas con los planos; reconstrucción geométrica a partir de documentación de diseño. | 0.2 | Muros segmentados con huecos reales para puertas y ventanas. | Envolvente exterior controlada por la planta de arquitectura; no se han modelado individualmente todas las capas de acabado. | Registro de líneas del PDF general, envolvente de 20 × 10 m; eje local 1 al norte y acceso del lado A al oeste. Estimación de trabajo de implantación de ±0,15 m, pendiente de CAD; no constituye una precisión topográfica garantizada. | Arquitectura | ARQ-OF-20260710 · Arquitectura A101 / p. 3, A103 / p. 5, A106 / p. 8; A301Cuadro de materiales | 285.95 | Arquitectura | Fábrica de bloques · acabado mineral claro | block_masonry | [0.843137,0.823529,0.772549] | 0.96 | 0 | Bloque hueco documentado. Apariencia mineral clara para distinguir el cerramiento; no confirma un revoco ni su espesor. | Arquitectura; BIM · Arquitectura | El plano general de 2026-07-31 mantiene el edificio de oficinas de 200 m², mientras documentación anterior indica su supresión. Se conserva lo dibujado, pendiente de confirmación de la propiedad y del equipo de diseño.
Edificio de oficinas · Fábrica de bloques huecos de hormigón de 200 mm · eje A · tramo 06 | Planos de arquitectura del edificio de oficinas | Bloque hueco de hormigón de árido ligero | 1.5 × 0.2 × 1.6 | 289.35 | 290.95 | 0.48 | office_0070 | yes | 0.402442 | 1.51326 | 1.6 | 6.04 | 0.48 | office | Edificio de oficinas | {"name":"Bloque hueco de hormigón de árido ligero","source":"ARQ-OF-20260710 · Arquitectura A101 / p. 3, A103 / p. 5, A106 / p. 8; A301Cuadro de materiales ","status":"known"} | {"documented":[{"label":"Espesor del muro","value":0.2,"unit":"m","source":"ARQ-OF-20260710 · Arquitectura A101 / p. 3, A103 / p. 5, A106 / p. 8; A301Cuadro de materiales ","status":"documentado"}],"geometry":[{"label":"Dimensiones de la caja local del elemento (X, Y, Z)","value":"1.5 × 0.2 × 1.6","unit":"m","source":"Malla triangulada del elemento en ejes locales del edificio","status":"derivado"},{"label":"Cota mínima absoluta de la malla","value":289.35,"unit":"m","source":"Malla de proyecto y origen altimétrico 285 m","status":"derivado"},{"label":"Cota máxima absoluta de la malla","value":290.95,"unit":"m","source":"Malla de proyecto y origen altimétrico 285 m","status":"derivado"},{"label":"Volumen geométrico bruto","value":0.48,"unit":"m³","source":"Malla cerrada del elemento","status":"derivado"}],"notes":["Las dimensiones documentadas proceden de anotaciones o cuadros; la caja y el volumen se calculan a partir de la malla.","El volumen es exclusivamente geométrico y bruto; no representa una medición neta de material ni una cantidad de compra."]} | {"documentId":"ARQ-OF-20260710","title":"Planos de arquitectura del edificio de oficinas","date":"2026-07-10","sheet":"Arquitectura A101 / p. 3, A103 / p. 5, A106 / p. 8; A301Cuadro de materiales "} | ["El plano general de 2026-07-31 mantiene el edificio de oficinas de 200 m², mientras documentación anterior indica su supresión. Se conserva lo dibujado, pendiente de confirmación de la propiedad y del equipo de diseño.","Envolvente exterior controlada por la planta de arquitectura; no se han modelado individualmente todas las capas de acabado.","Registro de líneas del PDF general, envolvente de 20 × 10 m; eje local 1 al norte y acceso del lado A al oeste. Estimación de trabajo de implantación de ±0,15 m, pendiente de CAD; no constituye una precisión topográfica garantizada."] | {"horizontalStatus":"derivado","verticalStatus":"derivado","baseElevationM":285.95,"note":"Registro de líneas del PDF general, envolvente de 20 × 10 m; eje local 1 al norte y acceso del lado A al oeste. Estimación de trabajo de implantación de ±0,15 m, pendiente de CAD; no constituye una precisión topográfica garantizada."} | {"Pset_WallCommon":{"IsExternal":{"value":true,"source":"ARQ-OF-20260710 · A101, A103 y alzados; elemento de la envolvente exterior identificada en planta","status":"known"}}} | {"boundingBoxM":{"min":[17.202125,90.413885,4.35],"max":[17.604567,91.927147,5.95]},"extentsM":[0.402442,1.513262,1.6],"meshSurfaceM2":6.039998,"meshVolumeM3":0.48,"closedSolid":true,"basis":"Geometría triangulada releída del IFC; envolventes y magnitudes no contractuales."} | {"material":true,"document":true,"quantities":true,"containerGuid":"3ztlotcerHPueDgxP84R6z","containerName":"Planta baja"} | {"id":"architecture","name":"Arquitectura"} | {"profileId":"block_masonry","name":"Fábrica de bloques · acabado mineral claro","materialName":"Bloque hueco de hormigón de árido ligero","physicalMaterialStatus":"known","physicalMaterialSource":"ARQ-OF-20260710 · Arquitectura A101 / p. 3, A103 / p. 5, A106 / p. 8; A301Cuadro de materiales ","appearanceStatus":"criterio_visual","appearanceBasis":"Bloque hueco documentado. Apariencia mineral clara para distinguir el cerramiento; no confirma un revoco ni su espesor.","note":"La apariencia gráfica no modifica ni confirma la especificación física del material."} | {"elementId":"office_0070","ifcGuid":"2JaioQunTG6enPCR0yrW7Z","ifcClass":"IfcWall","buildingId":"office","buildingName":"Edificio de oficinas","sourceDocumentId":"ARQ-OF-20260710","sourceRepresentationKind":"documentary_mesh"} | {"layerId":"architecture","layerName":"Arquitectura","role":"Muro","basis":"Clasificación por función del elemento; no modifica las especificaciones documentales."} | architecture | {"profileId":"block_masonry","name":"Fábrica de bloques · acabado mineral claro","status":"criterio_visual","basis":"Bloque hueco documentado. Apariencia mineral clara para distinguir el cerramiento; no confirma un revoco ni su espesor.","physicalMaterialUnchanged":true} | ARQ-OF-20260710 · Arquitectura A101 / p. 3, A103 / p. 5, A106 / p. 8; A301Cuadro de materiales | Dimensiones contrastadas con los planos; reconstrucción geométrica a partir de documentación de diseño. | 0.2 | Muros segmentados con huecos reales para puertas y ventanas. | Envolvente exterior controlada por la planta de arquitectura; no se han modelado individualmente todas las capas de acabado. | Registro de líneas del PDF general, envolvente de 20 × 10 m; eje local 1 al norte y acceso del lado A al oeste. Estimación de trabajo de implantación de ±0,15 m, pendiente de CAD; no constituye una precisión topográfica garantizada. | Arquitectura | ARQ-OF-20260710 · Arquitectura A101 / p. 3, A103 / p. 5, A106 / p. 8; A301Cuadro de materiales | 285.95 | Arquitectura | Fábrica de bloques · acabado mineral claro | block_masonry | [0.843137,0.823529,0.772549] | 0.96 | 0 | Bloque hueco documentado. Apariencia mineral clara para distinguir el cerramiento; no confirma un revoco ni su espesor. | Arquitectura; BIM · Arquitectura | El plano general de 2026-07-31 mantiene el edificio de oficinas de 200 m², mientras documentación anterior indica su supresión. Se conserva lo dibujado, pendiente de confirmación de la propiedad y del equipo de diseño.
Edificio de oficinas · Fábrica de bloques huecos de hormigón de 200 mm · eje A · tramo 07 | Planos de arquitectura del edificio de oficinas | Bloque hueco de hormigón de árido ligero | 2.55 × 0.2 × 1.1 | 285.95 | 287.05 | 0.561 | office_0071 | yes | 0.545456 | 2.55348 | 1.1 | 7.07 | 0.561 | office | Edificio de oficinas | {"name":"Bloque hueco de hormigón de árido ligero","source":"ARQ-OF-20260710 · Arquitectura A101 / p. 3, A103 / p. 5, A106 / p. 8; A301Cuadro de materiales ","status":"known"} | {"documented":[{"label":"Espesor del muro","value":0.2,"unit":"m","source":"ARQ-OF-20260710 · Arquitectura A101 / p. 3, A103 / p. 5, A106 / p. 8; A301Cuadro de materiales ","status":"documentado"}],"geometry":[{"label":"Dimensiones de la caja local del elemento (X, Y, Z)","value":"2.55 × 0.2 × 1.1","unit":"m","source":"Malla triangulada del elemento en ejes locales del edificio","status":"derivado"},{"label":"Cota mínima absoluta de la malla","value":285.95,"unit":"m","source":"Malla de proyecto y origen altimétrico 285 m","status":"derivado"},{"label":"Cota máxima absoluta de la malla","value":287.05,"unit":"m","source":"Malla de proyecto y origen altimétrico 285 m","status":"derivado"},{"label":"Volumen geométrico bruto","value":0.561,"unit":"m³","source":"Malla cerrada del elemento","status":"derivado"}],"notes":["Las dimensiones documentadas proceden de anotaciones o cuadros; la caja y el volumen se calculan a partir de la malla.","El volumen es exclusivamente geométrico y bruto; no representa una medición neta de material ni una cantidad de compra."]} | {"documentId":"ARQ-OF-20260710","title":"Planos de arquitectura del edificio de oficinas","date":"2026-07-10","sheet":"Arquitectura A101 / p. 3, A103 / p. 5, A106 / p. 8; A301Cuadro de materiales "} | ["El plano general de 2026-07-31 mantiene el edificio de oficinas de 200 m², mientras documentación anterior indica su supresión. Se conserva lo dibujado, pendiente de confirmación de la propiedad y del equipo de diseño.","Envolvente exterior controlada por la planta de arquitectura; no se han modelado individualmente todas las capas de acabado.","Registro de líneas del PDF general, envolvente de 20 × 10 m; eje local 1 al norte y acceso del lado A al oeste. Estimación de trabajo de implantación de ±0,15 m, pendiente de CAD; no constituye una precisión topográfica garantizada."] | {"horizontalStatus":"derivado","verticalStatus":"derivado","baseElevationM":285.95,"note":"Registro de líneas del PDF general, envolvente de 20 × 10 m; eje local 1 al norte y acceso del lado A al oeste. Estimación de trabajo de implantación de ±0,15 m, pendiente de CAD; no constituye una precisión topográfica garantizada."} | {"Pset_WallCommon":{"IsExternal":{"value":true,"source":"ARQ-OF-20260710 · A101, A103 y alzados; elemento de la envolvente exterior identificada en planta","status":"known"}}} | {"boundingBoxM":{"min":[16.854805,87.887649,0.95],"max":[17.400261,90.441126,2.05]},"extentsM":[0.545456,2.553477,1.1],"meshSurfaceM2":7.069999,"meshVolumeM3":0.561,"closedSolid":true,"basis":"Geometría triangulada releída del IFC; envolventes y magnitudes no contractuales."} | {"material":true,"document":true,"quantities":true,"containerGuid":"3ztlotcerHPueDgxP84R6z","containerName":"Planta baja"} | {"id":"architecture","name":"Arquitectura"} | {"profileId":"block_masonry","name":"Fábrica de bloques · acabado mineral claro","materialName":"Bloque hueco de hormigón de árido ligero","physicalMaterialStatus":"known","physicalMaterialSource":"ARQ-OF-20260710 · Arquitectura A101 / p. 3, A103 / p. 5, A106 / p. 8; A301Cuadro de materiales ","appearanceStatus":"criterio_visual","appearanceBasis":"Bloque hueco documentado. Apariencia mineral clara para distinguir el cerramiento; no confirma un revoco ni su espesor.","note":"La apariencia gráfica no modifica ni confirma la especificación física del material."} | {"elementId":"office_0071","ifcGuid":"0JJw4Or0zNPBqSgVtK8UA2","ifcClass":"IfcWall","buildingId":"office","buildingName":"Edificio de oficinas","sourceDocumentId":"ARQ-OF-20260710","sourceRepresentationKind":"documentary_mesh"} | {"layerId":"architecture","layerName":"Arquitectura","role":"Muro","basis":"Clasificación por función del elemento; no modifica las especificaciones documentales."} | architecture | {"profileId":"block_masonry","name":"Fábrica de bloques · acabado mineral claro","status":"criterio_visual","basis":"Bloque hueco documentado. Apariencia mineral clara para distinguir el cerramiento; no confirma un revoco ni su espesor.","physicalMaterialUnchanged":true} | ARQ-OF-20260710 · Arquitectura A101 / p. 3, A103 / p. 5, A106 / p. 8; A301Cuadro de materiales | Dimensiones contrastadas con los planos; reconstrucción geométrica a partir de documentación de diseño. | 0.2 | Muros segmentados con huecos reales para puertas y ventanas. | Envolvente exterior controlada por la planta de arquitectura; no se han modelado individualmente todas las capas de acabado. | Registro de líneas del PDF general, envolvente de 20 × 10 m; eje local 1 al norte y acceso del lado A al oeste. Estimación de trabajo de implantación de ±0,15 m, pendiente de CAD; no constituye una precisión topográfica garantizada. | Arquitectura | ARQ-OF-20260710 · Arquitectura A101 / p. 3, A103 / p. 5, A106 / p. 8; A301Cuadro de materiales | 285.95 | Arquitectura | Fábrica de bloques · acabado mineral claro | block_masonry | [0.843137,0.823529,0.772549] | 0.96 | 0 | Bloque hueco documentado. Apariencia mineral clara para distinguir el cerramiento; no confirma un revoco ni su espesor. | Arquitectura; BIM · Arquitectura | El plano general de 2026-07-31 mantiene el edificio de oficinas de 200 m², mientras documentación anterior indica su supresión. Se conserva lo dibujado, pendiente de confirmación de la propiedad y del equipo de diseño.
Edificio de oficinas · Fábrica de bloques huecos de hormigón de 200 mm · eje A · tramo 08 | Planos de arquitectura del edificio de oficinas | Bloque hueco de hormigón de árido ligero | 2.55 × 0.2 × 1.2 | 287.05 | 288.25 | 0.612 | office_0072 | yes | 0.545456 | 2.55348 | 1.2 | 7.62 | 0.612 | office | Edificio de oficinas | {"name":"Bloque hueco de hormigón de árido ligero","source":"ARQ-OF-20260710 · Arquitectura A101 / p. 3, A103 / p. 5, A106 / p. 8; A301Cuadro de materiales ","status":"known"} | {"documented":[{"label":"Espesor del muro","value":0.2,"unit":"m","source":"ARQ-OF-20260710 · Arquitectura A101 / p. 3, A103 / p. 5, A106 / p. 8; A301Cuadro de materiales ","status":"documentado"}],"geometry":[{"label":"Dimensiones de la caja local del elemento (X, Y, Z)","value":"2.55 × 0.2 × 1.2","unit":"m","source":"Malla triangulada del elemento en ejes locales del edificio","status":"derivado"},{"label":"Cota mínima absoluta de la malla","value":287.05,"unit":"m","source":"Malla de proyecto y origen altimétrico 285 m","status":"derivado"},{"label":"Cota máxima absoluta de la malla","value":288.25,"unit":"m","source":"Malla de proyecto y origen altimétrico 285 m","status":"derivado"},{"label":"Volumen geométrico bruto","value":0.612,"unit":"m³","source":"Malla cerrada del elemento","status":"derivado"}],"notes":["Las dimensiones documentadas proceden de anotaciones o cuadros; la caja y el volumen se calculan a partir de la malla.","El volumen es exclusivamente geométrico y bruto; no representa una medición neta de material ni una cantidad de compra."]} | {"documentId":"ARQ-OF-20260710","title":"Planos de arquitectura del edificio de oficinas","date":"2026-07-10","sheet":"Arquitectura A101 / p. 3, A103 / p. 5, A106 / p. 8; A301Cuadro de materiales "} | ["El plano general de 2026-07-31 mantiene el edificio de oficinas de 200 m², mientras documentación anterior indica su supresión. Se conserva lo dibujado, pendiente de confirmación de la propiedad y del equipo de diseño.","Envolvente exterior controlada por la planta de arquitectura; no se han modelado individualmente todas las capas de acabado.","Registro de líneas del PDF general, envolvente de 20 × 10 m; eje local 1 al norte y acceso del lado A al oeste. Estimación de trabajo de implantación de ±0,15 m, pendiente de CAD; no constituye una precisión topográfica garantizada."] | {"horizontalStatus":"derivado","verticalStatus":"derivado","baseElevationM":285.95,"note":"Registro de líneas del PDF general, envolvente de 20 × 10 m; eje local 1 al norte y acceso del lado A al oeste. Estimación de trabajo de implantación de ±0,15 m, pendiente de CAD; no constituye una precisión topográfica garantizada."} | {"Pset_WallCommon":{"IsExternal":{"value":true,"source":"ARQ-OF-20260710 · A101, A103 y alzados; elemento de la envolvente exterior identificada en planta","status":"known"}}} | {"boundingBoxM":{"min":[16.854805,87.887649,2.05],"max":[17.400261,90.441126,3.25]},"extentsM":[0.545456,2.553477,1.2],"meshSurfaceM2":7.619999,"meshVolumeM3":0.612,"closedSolid":true,"basis":"Geometría triangulada releída del IFC; envolventes y magnitudes no contractuales."} | {"material":true,"document":true,"quantities":true,"containerGuid":"3ztlotcerHPueDgxP84R6z","containerName":"Planta baja"} | {"id":"architecture","name":"Arquitectura"} | {"profileId":"block_masonry","name":"Fábrica de bloques · acabado mineral claro","materialName":"Bloque hueco de hormigón de árido ligero","physicalMaterialStatus":"known","physicalMaterialSource":"ARQ-OF-20260710 · Arquitectura A101 / p. 3, A103 / p. 5, A106 / p. 8; A301Cuadro de materiales ","appearanceStatus":"criterio_visual","appearanceBasis":"Bloque hueco documentado. Apariencia mineral clara para distinguir el cerramiento; no confirma un revoco ni su espesor.","note":"La apariencia gráfica no modifica ni confirma la especificación física del material."} | {"elementId":"office_0072","ifcGuid":"0eBL1XwzPMmgzYpgn2vdy_","ifcClass":"IfcWall","buildingId":"office","buildingName":"Edificio de oficinas","sourceDocumentId":"ARQ-OF-20260710","sourceRepresentationKind":"documentary_mesh"} | {"layerId":"architecture","layerName":"Arquitectura","role":"Muro","basis":"Clasificación por función del elemento; no modifica las especificaciones documentales."} | architecture | {"profileId":"block_masonry","name":"Fábrica de bloques · acabado mineral claro","status":"criterio_visual","basis":"Bloque hueco documentado. Apariencia mineral clara para distinguir el cerramiento; no confirma un revoco ni su espesor.","physicalMaterialUnchanged":true} | ARQ-OF-20260710 · Arquitectura A101 / p. 3, A103 / p. 5, A106 / p. 8; A301Cuadro de materiales | Dimensiones contrastadas con los planos; reconstrucción geométrica a partir de documentación de diseño. | 0.2 | Muros segmentados con huecos reales para puertas y ventanas. | Envolvente exterior controlada por la planta de arquitectura; no se han modelado individualmente todas las capas de acabado. | Registro de líneas del PDF general, envolvente de 20 × 10 m; eje local 1 al norte y acceso del lado A al oeste. Estimación de trabajo de implantación de ±0,15 m, pendiente de CAD; no constituye una precisión topográfica garantizada. | Arquitectura | ARQ-OF-20260710 · Arquitectura A101 / p. 3, A103 / p. 5, A106 / p. 8; A301Cuadro de materiales | 285.95 | Arquitectura | Fábrica de bloques · acabado mineral claro | block_masonry | [0.843137,0.823529,0.772549] | 0.96 | 0 | Bloque hueco documentado. Apariencia mineral clara para distinguir el cerramiento; no confirma un revoco ni su espesor. | Arquitectura; BIM · Arquitectura | El plano general de 2026-07-31 mantiene el edificio de oficinas de 200 m², mientras documentación anterior indica su supresión. Se conserva lo dibujado, pendiente de confirmación de la propiedad y del equipo de diseño.
Edificio de oficinas · Fábrica de bloques huecos de hormigón de 200 mm · eje A · tramo 09 | Planos de arquitectura del edificio de oficinas | Bloque hueco de hormigón de árido ligero | 2.55 × 0.2 × 1.1 | 288.25 | 289.35 | 0.561 | office_0073 | yes | 0.545456 | 2.55348 | 1.1 | 7.07 | 0.561 | office | Edificio de oficinas | {"name":"Bloque hueco de hormigón de árido ligero","source":"ARQ-OF-20260710 · Arquitectura A101 / p. 3, A103 / p. 5, A106 / p. 8; A301Cuadro de materiales ","status":"known"} | {"documented":[{"label":"Espesor del muro","value":0.2,"unit":"m","source":"ARQ-OF-20260710 · Arquitectura A101 / p. 3, A103 / p. 5, A106 / p. 8; A301Cuadro de materiales ","status":"documentado"}],"geometry":[{"label":"Dimensiones de la caja local del elemento (X, Y, Z)","value":"2.55 × 0.2 × 1.1","unit":"m","source":"Malla triangulada del elemento en ejes locales del edificio","status":"derivado"},{"label":"Cota mínima absoluta de la malla","value":288.25,"unit":"m","source":"Malla de proyecto y origen altimétrico 285 m","status":"derivado"},{"label":"Cota máxima absoluta de la malla","value":289.35,"unit":"m","source":"Malla de proyecto y origen altimétrico 285 m","status":"derivado"},{"label":"Volumen geométrico bruto","value":0.561,"unit":"m³","source":"Malla cerrada del elemento","status":"derivado"}],"notes":["Las dimensiones documentadas proceden de anotaciones o cuadros; la caja y el volumen se calculan a partir de la malla.","El volumen es exclusivamente geométrico y bruto; no representa una medición neta de material ni una cantidad de compra."]} | {"documentId":"ARQ-OF-20260710","title":"Planos de arquitectura del edificio de oficinas","date":"2026-07-10","sheet":"Arquitectura A101 / p. 3, A103 / p. 5, A106 / p. 8; A301Cuadro de materiales "} | ["El plano general de 2026-07-31 mantiene el edificio de oficinas de 200 m², mientras documentación anterior indica su supresión. Se conserva lo dibujado, pendiente de confirmación de la propiedad y del equipo de diseño.","Envolvente exterior controlada por la planta de arquitectura; no se han modelado individualmente todas las capas de acabado.","Registro de líneas del PDF general, envolvente de 20 × 10 m; eje local 1 al norte y acceso del lado A al oeste. Estimación de trabajo de implantación de ±0,15 m, pendiente de CAD; no constituye una precisión topográfica garantizada."] | {"horizontalStatus":"derivado","verticalStatus":"derivado","baseElevationM":285.95,"note":"Registro de líneas del PDF general, envolvente de 20 × 10 m; eje local 1 al norte y acceso del lado A al oeste. Estimación de trabajo de implantación de ±0,15 m, pendiente de CAD; no constituye una precisión topográfica garantizada."} | {"Pset_WallCommon":{"IsExternal":{"value":true,"source":"ARQ-OF-20260710 · A101, A103 y alzados; elemento de la envolvente exterior identificada en planta","status":"known"}}} | {"boundingBoxM":{"min":[16.854805,87.887649,3.25],"max":[17.400261,90.441126,4.35]},"extentsM":[0.545456,2.553477,1.1],"meshSurfaceM2":7.069999,"meshVolumeM3":0.561,"closedSolid":true,"basis":"Geometría triangulada releída del IFC; envolventes y magnitudes no contractuales."} | {"material":true,"document":true,"quantities":true,"containerGuid":"3ztlotcerHPueDgxP84R6z","containerName":"Planta baja"} | {"id":"architecture","name":"Arquitectura"} | {"profileId":"block_masonry","name":"Fábrica de bloques · acabado mineral claro","materialName":"Bloque hueco de hormigón de árido ligero","physicalMaterialStatus":"known","physicalMaterialSource":"ARQ-OF-20260710 · Arquitectura A101 / p. 3, A103 / p. 5, A106 / p. 8; A301Cuadro de materiales ","appearanceStatus":"criterio_visual","appearanceBasis":"Bloque hueco documentado. Apariencia mineral clara para distinguir el cerramiento; no confirma un revoco ni su espesor.","note":"La apariencia gráfica no modifica ni confirma la especificación física del material."} | {"elementId":"office_0073","ifcGuid":"3AavZATtrQWg97_BTMg2Fx","ifcClass":"IfcWall","buildingId":"office","buildingName":"Edificio de oficinas","sourceDocumentId":"ARQ-OF-20260710","sourceRepresentationKind":"documentary_mesh"} | {"layerId":"architecture","layerName":"Arquitectura","role":"Muro","basis":"Clasificación por función del elemento; no modifica las especificaciones documentales."} | architecture | {"profileId":"block_masonry","name":"Fábrica de bloques · acabado mineral claro","status":"criterio_visual","basis":"Bloque hueco documentado. Apariencia mineral clara para distinguir el cerramiento; no confirma un revoco ni su espesor.","physicalMaterialUnchanged":true} | ARQ-OF-20260710 · Arquitectura A101 / p. 3, A103 / p. 5, A106 / p. 8; A301Cuadro de materiales | Dimensiones contrastadas con los planos; reconstrucción geométrica a partir de documentación de diseño. | 0.2 | Muros segmentados con huecos reales para puertas y ventanas. | Envolvente exterior controlada por la planta de arquitectura; no se han modelado individualmente todas las capas de acabado. | Registro de líneas del PDF general, envolvente de 20 × 10 m; eje local 1 al norte y acceso del lado A al oeste. Estimación de trabajo de implantación de ±0,15 m, pendiente de CAD; no constituye una precisión topográfica garantizada. | Arquitectura | ARQ-OF-20260710 · Arquitectura A101 / p. 3, A103 / p. 5, A106 / p. 8; A301Cuadro de materiales | 285.95 | Arquitectura | Fábrica de bloques · acabado mineral claro | block_masonry | [0.843137,0.823529,0.772549] | 0.96 | 0 | Bloque hueco documentado. Apariencia mineral clara para distinguir el cerramiento; no confirma un revoco ni su espesor. | Arquitectura; BIM · Arquitectura | El plano general de 2026-07-31 mantiene el edificio de oficinas de 200 m², mientras documentación anterior indica su supresión. Se conserva lo dibujado, pendiente de confirmación de la propiedad y del equipo de diseño.
Edificio de oficinas · Fábrica de bloques huecos de hormigón de 200 mm · eje A · tramo 10 | Planos de arquitectura del edificio de oficinas | Bloque hueco de hormigón de árido ligero | 2.55 × 0.2 × 1.6 | 289.35 | 290.95 | 0.816 | office_0074 | yes | 0.545456 | 2.55348 | 1.6 | 9.82 | 0.815999 | office | Edificio de oficinas | {"name":"Bloque hueco de hormigón de árido ligero","source":"ARQ-OF-20260710 · Arquitectura A101 / p. 3, A103 / p. 5, A106 / p. 8; A301Cuadro de materiales ","status":"known"} | {"documented":[{"label":"Espesor del muro","value":0.2,"unit":"m","source":"ARQ-OF-20260710 · Arquitectura A101 / p. 3, A103 / p. 5, A106 / p. 8; A301Cuadro de materiales ","status":"documentado"}],"geometry":[{"label":"Dimensiones de la caja local del elemento (X, Y, Z)","value":"2.55 × 0.2 × 1.6","unit":"m","source":"Malla triangulada del elemento en ejes locales del edificio","status":"derivado"},{"label":"Cota mínima absoluta de la malla","value":289.35,"unit":"m","source":"Malla de proyecto y origen altimétrico 285 m","status":"derivado"},{"label":"Cota máxima absoluta de la malla","value":290.95,"unit":"m","source":"Malla de proyecto y origen altimétrico 285 m","status":"derivado"},{"label":"Volumen geométrico bruto","value":0.816,"unit":"m³","source":"Malla cerrada del elemento","status":"derivado"}],"notes":["Las dimensiones documentadas proceden de anotaciones o cuadros; la caja y el volumen se calculan a partir de la malla.","El volumen es exclusivamente geométrico y bruto; no representa una medición neta de material ni una cantidad de compra."]} | {"documentId":"ARQ-OF-20260710","title":"Planos de arquitectura del edificio de oficinas","date":"2026-07-10","sheet":"Arquitectura A101 / p. 3, A103 / p. 5, A106 / p. 8; A301Cuadro de materiales "} | ["El plano general de 2026-07-31 mantiene el edificio de oficinas de 200 m², mientras documentación anterior indica su supresión. Se conserva lo dibujado, pendiente de confirmación de la propiedad y del equipo de diseño.","Envolvente exterior controlada por la planta de arquitectura; no se han modelado individualmente todas las capas de acabado.","Registro de líneas del PDF general, envolvente de 20 × 10 m; eje local 1 al norte y acceso del lado A al oeste. Estimación de trabajo de implantación de ±0,15 m, pendiente de CAD; no constituye una precisión topográfica garantizada."] | {"horizontalStatus":"derivado","verticalStatus":"derivado","baseElevationM":285.95,"note":"Registro de líneas del PDF general, envolvente de 20 × 10 m; eje local 1 al norte y acceso del lado A al oeste. Estimación de trabajo de implantación de ±0,15 m, pendiente de CAD; no constituye una precisión topográfica garantizada."} | {"Pset_WallCommon":{"IsExternal":{"value":true,"source":"ARQ-OF-20260710 · A101, A103 y alzados; elemento de la envolvente exterior identificada en planta","status":"known"}}} | {"boundingBoxM":{"min":[16.854805,87.887649,4.35],"max":[17.400261,90.441126,5.95]},"extentsM":[0.545456,2.553477,1.6],"meshSurfaceM2":9.819999,"meshVolumeM3":0.815999,"closedSolid":true,"basis":"Geometría triangulada releída del IFC; envolventes y magnitudes no contractuales."} | {"material":true,"document":true,"quantities":true,"containerGuid":"3ztlotcerHPueDgxP84R6z","containerName":"Planta baja"} | {"id":"architecture","name":"Arquitectura"} | {"profileId":"block_masonry","name":"Fábrica de bloques · acabado mineral claro","materialName":"Bloque hueco de hormigón de árido ligero","physicalMaterialStatus":"known","physicalMaterialSource":"ARQ-OF-20260710 · Arquitectura A101 / p. 3, A103 / p. 5, A106 / p. 8; A301Cuadro de materiales ","appearanceStatus":"criterio_visual","appearanceBasis":"Bloque hueco documentado. Apariencia mineral clara para distinguir el cerramiento; no confirma un revoco ni su espesor.","note":"La apariencia gráfica no modifica ni confirma la especificación física del material."} | {"elementId":"office_0074","ifcGuid":"36fieXivXQXfvTCF_v$Opn","ifcClass":"IfcWall","buildingId":"office","buildingName":"Edificio de oficinas","sourceDocumentId":"ARQ-OF-20260710","sourceRepresentationKind":"documentary_mesh"} | {"layerId":"architecture","layerName":"Arquitectura","role":"Muro","basis":"Clasificación por función del elemento; no modifica las especificaciones documentales."} | architecture | {"profileId":"block_masonry","name":"Fábrica de bloques · acabado mineral claro","status":"criterio_visual","basis":"Bloque hueco documentado. Apariencia mineral clara para distinguir el cerramiento; no confirma un revoco ni su espesor.","physicalMaterialUnchanged":true} | ARQ-OF-20260710 · Arquitectura A101 / p. 3, A103 / p. 5, A106 / p. 8; A301Cuadro de materiales | Dimensiones contrastadas con los planos; reconstrucción geométrica a partir de documentación de diseño. | 0.2 | Muros segmentados con huecos reales para puertas y ventanas. | Envolvente exterior controlada por la planta de arquitectura; no se han modelado individualmente todas las capas de acabado. | Registro de líneas del PDF general, envolvente de 20 × 10 m; eje local 1 al norte y acceso del lado A al oeste. Estimación de trabajo de implantación de ±0,15 m, pendiente de CAD; no constituye una precisión topográfica garantizada. | Arquitectura | ARQ-OF-20260710 · Arquitectura A101 / p. 3, A103 / p. 5, A106 / p. 8; A301Cuadro de materiales | 285.95 | Arquitectura | Fábrica de bloques · acabado mineral claro | block_masonry | [0.843137,0.823529,0.772549] | 0.96 | 0 | Bloque hueco documentado. Apariencia mineral clara para distinguir el cerramiento; no confirma un revoco ni su espesor. | Arquitectura; BIM · Arquitectura | El plano general de 2026-07-31 mantiene el edificio de oficinas de 200 m², mientras documentación anterior indica su supresión. Se conserva lo dibujado, pendiente de confirmación de la propiedad y del equipo de diseño.
Edificio de oficinas · Fábrica de bloques huecos de hormigón de 200 mm · eje A · tramo 11 | Planos de arquitectura del edificio de oficinas | Bloque hueco de hormigón de árido ligero | 0.9 × 0.2 × 1.1 | 285.95 | 287.05 | 0.198 | office_0075 | yes | 0.320719 | 0.918854 | 1.1 | 2.78 | 0.198 | office | Edificio de oficinas | {"name":"Bloque hueco de hormigón de árido ligero","source":"ARQ-OF-20260710 · Arquitectura A101 / p. 3, A103 / p. 5, A106 / p. 8; A301Cuadro de materiales ","status":"known"} | {"documented":[{"label":"Espesor del muro","value":0.2,"unit":"m","source":"ARQ-OF-20260710 · Arquitectura A101 / p. 3, A103 / p. 5, A106 / p. 8; A301Cuadro de materiales ","status":"documentado"}],"geometry":[{"label":"Dimensiones de la caja local del elemento (X, Y, Z)","value":"0.9 × 0.2 × 1.1","unit":"m","source":"Malla triangulada del elemento en ejes locales del edificio","status":"derivado"},{"label":"Cota mínima absoluta de la malla","value":285.95,"unit":"m","source":"Malla de proyecto y origen altimétrico 285 m","status":"derivado"},{"label":"Cota máxima absoluta de la malla","value":287.05,"unit":"m","source":"Malla de proyecto y origen altimétrico 285 m","status":"derivado"},{"label":"Volumen geométrico bruto","value":0.198,"unit":"m³","source":"Malla cerrada del elemento","status":"derivado"}],"notes":["Las dimensiones documentadas proceden de anotaciones o cuadros; la caja y el volumen se calculan a partir de la malla.","El volumen es exclusivamente geométrico y bruto; no representa una medición neta de material ni una cantidad de compra."]} | {"documentId":"ARQ-OF-20260710","title":"Planos de arquitectura del edificio de oficinas","date":"2026-07-10","sheet":"Arquitectura A101 / p. 3, A103 / p. 5, A106 / p. 8; A301Cuadro de materiales "} | ["El plano general de 2026-07-31 mantiene el edificio de oficinas de 200 m², mientras documentación anterior indica su supresión. Se conserva lo dibujado, pendiente de confirmación de la propiedad y del equipo de diseño.","Envolvente exterior controlada por la planta de arquitectura; no se han modelado individualmente todas las capas de acabado.","Registro de líneas del PDF general, envolvente de 20 × 10 m; eje local 1 al norte y acceso del lado A al oeste. Estimación de trabajo de implantación de ±0,15 m, pendiente de CAD; no constituye una precisión topográfica garantizada."] | {"horizontalStatus":"derivado","verticalStatus":"derivado","baseElevationM":285.95,"note":"Registro de líneas del PDF general, envolvente de 20 × 10 m; eje local 1 al norte y acceso del lado A al oeste. Estimación de trabajo de implantación de ±0,15 m, pendiente de CAD; no constituye una precisión topográfica garantizada."} | {"Pset_WallCommon":{"IsExternal":{"value":true,"source":"ARQ-OF-20260710 · A101, A103 y alzados; elemento de la envolvente exterior identificada en planta","status":"known"}}} | {"boundingBoxM":{"min":[16.732222,86.996036,0.95],"max":[17.052941,87.91489,2.05]},"extentsM":[0.320719,0.918854,1.1],"meshSurfaceM2":2.78,"meshVolumeM3":0.198,"closedSolid":true,"basis":"Geometría triangulada releída del IFC; envolventes y magnitudes no contractuales."} | {"material":true,"document":true,"quantities":true,"containerGuid":"3ztlotcerHPueDgxP84R6z","containerName":"Planta baja"} | {"id":"architecture","name":"Arquitectura"} | {"profileId":"block_masonry","name":"Fábrica de bloques · acabado mineral claro","materialName":"Bloque hueco de hormigón de árido ligero","physicalMaterialStatus":"known","physicalMaterialSource":"ARQ-OF-20260710 · Arquitectura A101 / p. 3, A103 / p. 5, A106 / p. 8; A301Cuadro de materiales ","appearanceStatus":"criterio_visual","appearanceBasis":"Bloque hueco documentado. Apariencia mineral clara para distinguir el cerramiento; no confirma un revoco ni su espesor.","note":"La apariencia gráfica no modifica ni confirma la especificación física del material."} | {"elementId":"office_0075","ifcGuid":"20RUjdrHXQrPW7no8s8VsA","ifcClass":"IfcWall","buildingId":"office","buildingName":"Edificio de oficinas","sourceDocumentId":"ARQ-OF-20260710","sourceRepresentationKind":"documentary_mesh"} | {"layerId":"architecture","layerName":"Arquitectura","role":"Muro","basis":"Clasificación por función del elemento; no modifica las especificaciones documentales."} | architecture | {"profileId":"block_masonry","name":"Fábrica de bloques · acabado mineral claro","status":"criterio_visual","basis":"Bloque hueco documentado. Apariencia mineral clara para distinguir el cerramiento; no confirma un revoco ni su espesor.","physicalMaterialUnchanged":true} | ARQ-OF-20260710 · Arquitectura A101 / p. 3, A103 / p. 5, A106 / p. 8; A301Cuadro de materiales | Dimensiones contrastadas con los planos; reconstrucción geométrica a partir de documentación de diseño. | 0.2 | Muros segmentados con huecos reales para puertas y ventanas. | Envolvente exterior controlada por la planta de arquitectura; no se han modelado individualmente todas las capas de acabado. | Registro de líneas del PDF general, envolvente de 20 × 10 m; eje local 1 al norte y acceso del lado A al oeste. Estimación de trabajo de implantación de ±0,15 m, pendiente de CAD; no constituye una precisión topográfica garantizada. | Arquitectura | ARQ-OF-20260710 · Arquitectura A101 / p. 3, A103 / p. 5, A106 / p. 8; A301Cuadro de materiales | 285.95 | Arquitectura | Fábrica de bloques · acabado mineral claro | block_masonry | [0.843137,0.823529,0.772549] | 0.96 | 0 | Bloque hueco documentado. Apariencia mineral clara para distinguir el cerramiento; no confirma un revoco ni su espesor. | Arquitectura; BIM · Arquitectura | El plano general de 2026-07-31 mantiene el edificio de oficinas de 200 m², mientras documentación anterior indica su supresión. Se conserva lo dibujado, pendiente de confirmación de la propiedad y del equipo de diseño.
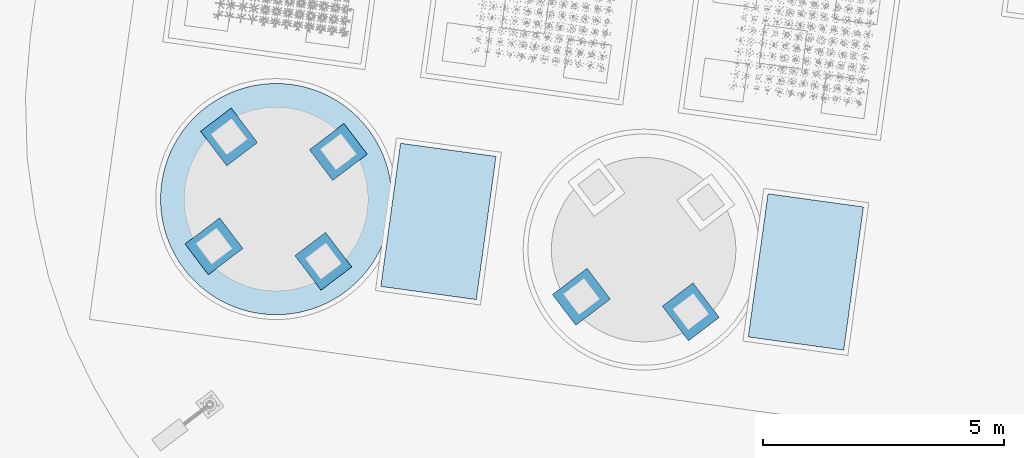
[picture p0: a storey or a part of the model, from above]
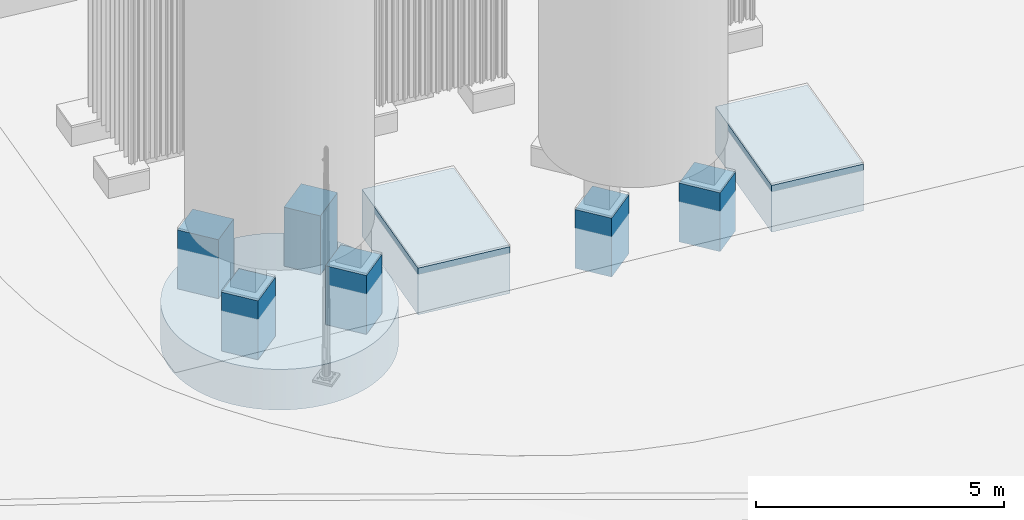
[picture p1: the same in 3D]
Properties of the parts of a building model (IFC4), part 119 of 134

# IfcWall (187)
Name | Document | Material = JH_Trazabilidad, Material = name | Dimensiones de la caja local del elemento (X, Y, Z) | Cota mínima absoluta de la malla (m) | Cota máxima absoluta de la malla (m) | Volumen geométrico bruto (m3) = Volumen geométrico (m³) | Reference = Identificador del elemento = Identificador | IsExternal | ExtensionX (m) | ExtensionY (m) | ExtensionZ (m) | SuperficieDeLaMalla (m2) | VolumenGeometrico (m3) = GrossVolume (m3) | buildingId | buildingName = Edificio | material | dimensions | JH_InformacionBIM, source = DocumentoFuente | issues = IncidenciasPendientes | positioning = PosicionYEstado | commonProperties | geometryMetrics | ifcAssociations | visualLayer | materialAppearance | visualizationIdentity | classification | layerId = IdentificadorCapa | appearance | Planos de referencia | Base geométrica | Espesor del muro (m) = Espesor del muro (m) | Tratamiento de los huecos | Representación de los acabados | Estado de la implantación | Disciplina | Referencia del material = JH_EvidenciaDeMaterial, source | Cota de planta baja terminada (m) | Capa BIM = NombreCapa | Acabado de visualización = Acabado | Perfil | ColorRGB | Rugosidad | Metallicidad | Referencia | Group | Discrepancia entre versiones
Edificio de oficinas · Fábrica de bloques huecos de hormigón de 200 mm · eje A · tramo 22 | Planos de arquitectura del edificio de oficinas | Bloque hueco de hormigón de árido ligero | 0.9 × 0.2 × 1.6 | 289.35 | 290.95 | 0.288 | office_0086 | yes | 0.32072 | 0.918853 | 1.6 | 3.88 | 0.288 | office | Edificio de oficinas | {"name":"Bloque hueco de hormigón de árido ligero","source":"ARQ-OF-20260710 · Arquitectura A101 / p. 3, A103 / p. 5, A106 / p. 8; A301Cuadro de materiales ","status":"known"} | {"documented":[{"label":"Espesor del muro","value":0.2,"unit":"m","source":"ARQ-OF-20260710 · Arquitectura A101 / p. 3, A103 / p. 5, A106 / p. 8; A301Cuadro de materiales ","status":"documentado"}],"geometry":[{"label":"Dimensiones de la caja local del elemento (X, Y, Z)","value":"0.9 × 0.2 × 1.6","unit":"m","source":"Malla triangulada del elemento en ejes locales del edificio","status":"derivado"},{"label":"Cota mínima absoluta de la malla","value":289.35,"unit":"m","source":"Malla de proyecto y origen altimétrico 285 m","status":"derivado"},{"label":"Cota máxima absoluta de la malla","value":290.95,"unit":"m","source":"Malla de proyecto y origen altimétrico 285 m","status":"derivado"},{"label":"Volumen geométrico bruto","value":0.288,"unit":"m³","source":"Malla cerrada del elemento","status":"derivado"}],"notes":["Las dimensiones documentadas proceden de anotaciones o cuadros; la caja y el volumen se calculan a partir de la malla.","El volumen es exclusivamente geométrico y bruto; no representa una medición neta de material ni una cantidad de compra."]} | {"documentId":"ARQ-OF-20260710","title":"Planos de arquitectura del edificio de oficinas","date":"2026-07-10","sheet":"Arquitectura A101 / p. 3, A103 / p. 5, A106 / p. 8; A301Cuadro de materiales "} | ["El plano general de 2026-07-31 mantiene el edificio de oficinas de 200 m², mientras documentación anterior indica su supresión. Se conserva lo dibujado, pendiente de confirmación de la propiedad y del equipo de diseño.","Envolvente exterior controlada por la planta de arquitectura; no se han modelado individualmente todas las capas de acabado.","Registro de líneas del PDF general, envolvente de 20 × 10 m; eje local 1 al norte y acceso del lado A al oeste. Estimación de trabajo de implantación de ±0,15 m, pendiente de CAD; no constituye una precisión topográfica garantizada."] | {"horizontalStatus":"derivado","verticalStatus":"derivado","baseElevationM":285.95,"note":"Registro de líneas del PDF general, envolvente de 20 × 10 m; eje local 1 al norte y acceso del lado A al oeste. Estimación de trabajo de implantación de ±0,15 m, pendiente de CAD; no constituye una precisión topográfica garantizada."} | {"Pset_WallCommon":{"IsExternal":{"value":true,"source":"ARQ-OF-20260710 · A101, A103 y alzados; elemento de la envolvente exterior identificada en planta","status":"known"}}} | {"boundingBoxM":{"min":[16.364471,84.321198,4.35],"max":[16.685191,85.240051,5.95]},"extentsM":[0.32072,0.918853,1.6],"meshSurfaceM2":3.879998,"meshVolumeM3":0.288,"closedSolid":true,"basis":"Geometría triangulada releída del IFC; envolventes y magnitudes no contractuales."} | {"material":true,"document":true,"quantities":true,"containerGuid":"3ztlotcerHPueDgxP84R6z","containerName":"Planta baja"} | {"id":"architecture","name":"Arquitectura"} | {"profileId":"block_masonry","name":"Fábrica de bloques · acabado mineral claro","materialName":"Bloque hueco de hormigón de árido ligero","physicalMaterialStatus":"known","physicalMaterialSource":"ARQ-OF-20260710 · Arquitectura A101 / p. 3, A103 / p. 5, A106 / p. 8; A301Cuadro de materiales ","appearanceStatus":"criterio_visual","appearanceBasis":"Bloque hueco documentado. Apariencia mineral clara para distinguir el cerramiento; no confirma un revoco ni su espesor.","note":"La apariencia gráfica no modifica ni confirma la especificación física del material."} | {"elementId":"office_0086","ifcGuid":"3x2Hds67rNIRaU9OiwJRAM","ifcClass":"IfcWall","buildingId":"office","buildingName":"Edificio de oficinas","sourceDocumentId":"ARQ-OF-20260710","sourceRepresentationKind":"documentary_mesh"} | {"layerId":"architecture","layerName":"Arquitectura","role":"Muro","basis":"Clasificación por función del elemento; no modifica las especificaciones documentales."} | architecture | {"profileId":"block_masonry","name":"Fábrica de bloques · acabado mineral claro","status":"criterio_visual","basis":"Bloque hueco documentado. Apariencia mineral clara para distinguir el cerramiento; no confirma un revoco ni su espesor.","physicalMaterialUnchanged":true} | ARQ-OF-20260710 · Arquitectura A101 / p. 3, A103 / p. 5, A106 / p. 8; A301Cuadro de materiales | Dimensiones contrastadas con los planos; reconstrucción geométrica a partir de documentación de diseño. | 0.2 | Muros segmentados con huecos reales para puertas y ventanas. | Envolvente exterior controlada por la planta de arquitectura; no se han modelado individualmente todas las capas de acabado. | Registro de líneas del PDF general, envolvente de 20 × 10 m; eje local 1 al norte y acceso del lado A al oeste. Estimación de trabajo de implantación de ±0,15 m, pendiente de CAD; no constituye una precisión topográfica garantizada. | Arquitectura | ARQ-OF-20260710 · Arquitectura A101 / p. 3, A103 / p. 5, A106 / p. 8; A301Cuadro de materiales | 285.95 | Arquitectura | Fábrica de bloques · acabado mineral claro | block_masonry | [0.843137,0.823529,0.772549] | 0.96 | 0 | Bloque hueco documentado. Apariencia mineral clara para distinguir el cerramiento; no confirma un revoco ni su espesor. | Arquitectura; BIM · Arquitectura | El plano general de 2026-07-31 mantiene el edificio de oficinas de 200 m², mientras documentación anterior indica su supresión. Se conserva lo dibujado, pendiente de confirmación de la propiedad y del equipo de diseño.
Edificio de oficinas · Fábrica de bloques huecos de hormigón de 200 mm · eje A · tramo 23 | Planos de arquitectura del edificio de oficinas | Bloque hueco de hormigón de árido ligero | 0.9 × 0.2 × 1.1 | 285.95 | 287.05 | 0.198 | office_0087 | yes | 0.320719 | 0.918854 | 1.1 | 2.78 | 0.198 | office | Edificio de oficinas | {"name":"Bloque hueco de hormigón de árido ligero","source":"ARQ-OF-20260710 · Arquitectura A101 / p. 3, A103 / p. 5, A106 / p. 8; A301Cuadro de materiales ","status":"known"} | {"documented":[{"label":"Espesor del muro","value":0.2,"unit":"m","source":"ARQ-OF-20260710 · Arquitectura A101 / p. 3, A103 / p. 5, A106 / p. 8; A301Cuadro de materiales ","status":"documentado"}],"geometry":[{"label":"Dimensiones de la caja local del elemento (X, Y, Z)","value":"0.9 × 0.2 × 1.1","unit":"m","source":"Malla triangulada del elemento en ejes locales del edificio","status":"derivado"},{"label":"Cota mínima absoluta de la malla","value":285.95,"unit":"m","source":"Malla de proyecto y origen altimétrico 285 m","status":"derivado"},{"label":"Cota máxima absoluta de la malla","value":287.05,"unit":"m","source":"Malla de proyecto y origen altimétrico 285 m","status":"derivado"},{"label":"Volumen geométrico bruto","value":0.198,"unit":"m³","source":"Malla cerrada del elemento","status":"derivado"}],"notes":["Las dimensiones documentadas proceden de anotaciones o cuadros; la caja y el volumen se calculan a partir de la malla.","El volumen es exclusivamente geométrico y bruto; no representa una medición neta de material ni una cantidad de compra."]} | {"documentId":"ARQ-OF-20260710","title":"Planos de arquitectura del edificio de oficinas","date":"2026-07-10","sheet":"Arquitectura A101 / p. 3, A103 / p. 5, A106 / p. 8; A301Cuadro de materiales "} | ["El plano general de 2026-07-31 mantiene el edificio de oficinas de 200 m², mientras documentación anterior indica su supresión. Se conserva lo dibujado, pendiente de confirmación de la propiedad y del equipo de diseño.","Envolvente exterior controlada por la planta de arquitectura; no se han modelado individualmente todas las capas de acabado.","Registro de líneas del PDF general, envolvente de 20 × 10 m; eje local 1 al norte y acceso del lado A al oeste. Estimación de trabajo de implantación de ±0,15 m, pendiente de CAD; no constituye una precisión topográfica garantizada."] | {"horizontalStatus":"derivado","verticalStatus":"derivado","baseElevationM":285.95,"note":"Registro de líneas del PDF general, envolvente de 20 × 10 m; eje local 1 al norte y acceso del lado A al oeste. Estimación de trabajo de implantación de ±0,15 m, pendiente de CAD; no constituye una precisión topográfica garantizada."} | {"Pset_WallCommon":{"IsExternal":{"value":true,"source":"ARQ-OF-20260710 · A101, A103 y alzados; elemento de la envolvente exterior identificada en planta","status":"known"}}} | {"boundingBoxM":{"min":[16.241888,83.429585,0.95],"max":[16.562607,84.348439,2.05]},"extentsM":[0.320719,0.918854,1.1],"meshSurfaceM2":2.78,"meshVolumeM3":0.198,"closedSolid":true,"basis":"Geometría triangulada releída del IFC; envolventes y magnitudes no contractuales."} | {"material":true,"document":true,"quantities":true,"containerGuid":"3ztlotcerHPueDgxP84R6z","containerName":"Planta baja"} | {"id":"architecture","name":"Arquitectura"} | {"profileId":"block_masonry","name":"Fábrica de bloques · acabado mineral claro","materialName":"Bloque hueco de hormigón de árido ligero","physicalMaterialStatus":"known","physicalMaterialSource":"ARQ-OF-20260710 · Arquitectura A101 / p. 3, A103 / p. 5, A106 / p. 8; A301Cuadro de materiales ","appearanceStatus":"criterio_visual","appearanceBasis":"Bloque hueco documentado. Apariencia mineral clara para distinguir el cerramiento; no confirma un revoco ni su espesor.","note":"La apariencia gráfica no modifica ni confirma la especificación física del material."} | {"elementId":"office_0087","ifcGuid":"0Np14euJLL2fOnaccngm2n","ifcClass":"IfcWall","buildingId":"office","buildingName":"Edificio de oficinas","sourceDocumentId":"ARQ-OF-20260710","sourceRepresentationKind":"documentary_mesh"} | {"layerId":"architecture","layerName":"Arquitectura","role":"Muro","basis":"Clasificación por función del elemento; no modifica las especificaciones documentales."} | architecture | {"profileId":"block_masonry","name":"Fábrica de bloques · acabado mineral claro","status":"criterio_visual","basis":"Bloque hueco documentado. Apariencia mineral clara para distinguir el cerramiento; no confirma un revoco ni su espesor.","physicalMaterialUnchanged":true} | ARQ-OF-20260710 · Arquitectura A101 / p. 3, A103 / p. 5, A106 / p. 8; A301Cuadro de materiales | Dimensiones contrastadas con los planos; reconstrucción geométrica a partir de documentación de diseño. | 0.2 | Muros segmentados con huecos reales para puertas y ventanas. | Envolvente exterior controlada por la planta de arquitectura; no se han modelado individualmente todas las capas de acabado. | Registro de líneas del PDF general, envolvente de 20 × 10 m; eje local 1 al norte y acceso del lado A al oeste. Estimación de trabajo de implantación de ±0,15 m, pendiente de CAD; no constituye una precisión topográfica garantizada. | Arquitectura | ARQ-OF-20260710 · Arquitectura A101 / p. 3, A103 / p. 5, A106 / p. 8; A301Cuadro de materiales | 285.95 | Arquitectura | Fábrica de bloques · acabado mineral claro | block_masonry | [0.843137,0.823529,0.772549] | 0.96 | 0 | Bloque hueco documentado. Apariencia mineral clara para distinguir el cerramiento; no confirma un revoco ni su espesor. | Arquitectura; BIM · Arquitectura | El plano general de 2026-07-31 mantiene el edificio de oficinas de 200 m², mientras documentación anterior indica su supresión. Se conserva lo dibujado, pendiente de confirmación de la propiedad y del equipo de diseño.
Edificio de oficinas · Fábrica de bloques huecos de hormigón de 200 mm · eje A · tramo 24 | Planos de arquitectura del edificio de oficinas | Bloque hueco de hormigón de árido ligero | 0.9 × 0.2 × 1.6 | 289.35 | 290.95 | 0.288 | office_0088 | yes | 0.320719 | 0.918854 | 1.6 | 3.88 | 0.288 | office | Edificio de oficinas | {"name":"Bloque hueco de hormigón de árido ligero","source":"ARQ-OF-20260710 · Arquitectura A101 / p. 3, A103 / p. 5, A106 / p. 8; A301Cuadro de materiales ","status":"known"} | {"documented":[{"label":"Espesor del muro","value":0.2,"unit":"m","source":"ARQ-OF-20260710 · Arquitectura A101 / p. 3, A103 / p. 5, A106 / p. 8; A301Cuadro de materiales ","status":"documentado"}],"geometry":[{"label":"Dimensiones de la caja local del elemento (X, Y, Z)","value":"0.9 × 0.2 × 1.6","unit":"m","source":"Malla triangulada del elemento en ejes locales del edificio","status":"derivado"},{"label":"Cota mínima absoluta de la malla","value":289.35,"unit":"m","source":"Malla de proyecto y origen altimétrico 285 m","status":"derivado"},{"label":"Cota máxima absoluta de la malla","value":290.95,"unit":"m","source":"Malla de proyecto y origen altimétrico 285 m","status":"derivado"},{"label":"Volumen geométrico bruto","value":0.288,"unit":"m³","source":"Malla cerrada del elemento","status":"derivado"}],"notes":["Las dimensiones documentadas proceden de anotaciones o cuadros; la caja y el volumen se calculan a partir de la malla.","El volumen es exclusivamente geométrico y bruto; no representa una medición neta de material ni una cantidad de compra."]} | {"documentId":"ARQ-OF-20260710","title":"Planos de arquitectura del edificio de oficinas","date":"2026-07-10","sheet":"Arquitectura A101 / p. 3, A103 / p. 5, A106 / p. 8; A301Cuadro de materiales "} | ["El plano general de 2026-07-31 mantiene el edificio de oficinas de 200 m², mientras documentación anterior indica su supresión. Se conserva lo dibujado, pendiente de confirmación de la propiedad y del equipo de diseño.","Envolvente exterior controlada por la planta de arquitectura; no se han modelado individualmente todas las capas de acabado.","Registro de líneas del PDF general, envolvente de 20 × 10 m; eje local 1 al norte y acceso del lado A al oeste. Estimación de trabajo de implantación de ±0,15 m, pendiente de CAD; no constituye una precisión topográfica garantizada."] | {"horizontalStatus":"derivado","verticalStatus":"derivado","baseElevationM":285.95,"note":"Registro de líneas del PDF general, envolvente de 20 × 10 m; eje local 1 al norte y acceso del lado A al oeste. Estimación de trabajo de implantación de ±0,15 m, pendiente de CAD; no constituye una precisión topográfica garantizada."} | {"Pset_WallCommon":{"IsExternal":{"value":true,"source":"ARQ-OF-20260710 · A101, A103 y alzados; elemento de la envolvente exterior identificada en planta","status":"known"}}} | {"boundingBoxM":{"min":[16.241888,83.429585,4.35],"max":[16.562607,84.348439,5.95]},"extentsM":[0.320719,0.918854,1.6],"meshSurfaceM2":3.88,"meshVolumeM3":0.288,"closedSolid":true,"basis":"Geometría triangulada releída del IFC; envolventes y magnitudes no contractuales."} | {"material":true,"document":true,"quantities":true,"containerGuid":"3ztlotcerHPueDgxP84R6z","containerName":"Planta baja"} | {"id":"architecture","name":"Arquitectura"} | {"profileId":"block_masonry","name":"Fábrica de bloques · acabado mineral claro","materialName":"Bloque hueco de hormigón de árido ligero","physicalMaterialStatus":"known","physicalMaterialSource":"ARQ-OF-20260710 · Arquitectura A101 / p. 3, A103 / p. 5, A106 / p. 8; A301Cuadro de materiales ","appearanceStatus":"criterio_visual","appearanceBasis":"Bloque hueco documentado. Apariencia mineral clara para distinguir el cerramiento; no confirma un revoco ni su espesor.","note":"La apariencia gráfica no modifica ni confirma la especificación física del material."} | {"elementId":"office_0088","ifcGuid":"29290mf61S5BaQ$2LoG3TV","ifcClass":"IfcWall","buildingId":"office","buildingName":"Edificio de oficinas","sourceDocumentId":"ARQ-OF-20260710","sourceRepresentationKind":"documentary_mesh"} | {"layerId":"architecture","layerName":"Arquitectura","role":"Muro","basis":"Clasificación por función del elemento; no modifica las especificaciones documentales."} | architecture | {"profileId":"block_masonry","name":"Fábrica de bloques · acabado mineral claro","status":"criterio_visual","basis":"Bloque hueco documentado. Apariencia mineral clara para distinguir el cerramiento; no confirma un revoco ni su espesor.","physicalMaterialUnchanged":true} | ARQ-OF-20260710 · Arquitectura A101 / p. 3, A103 / p. 5, A106 / p. 8; A301Cuadro de materiales | Dimensiones contrastadas con los planos; reconstrucción geométrica a partir de documentación de diseño. | 0.2 | Muros segmentados con huecos reales para puertas y ventanas. | Envolvente exterior controlada por la planta de arquitectura; no se han modelado individualmente todas las capas de acabado. | Registro de líneas del PDF general, envolvente de 20 × 10 m; eje local 1 al norte y acceso del lado A al oeste. Estimación de trabajo de implantación de ±0,15 m, pendiente de CAD; no constituye una precisión topográfica garantizada. | Arquitectura | ARQ-OF-20260710 · Arquitectura A101 / p. 3, A103 / p. 5, A106 / p. 8; A301Cuadro de materiales | 285.95 | Arquitectura | Fábrica de bloques · acabado mineral claro | block_masonry | [0.843137,0.823529,0.772549] | 0.96 | 0 | Bloque hueco documentado. Apariencia mineral clara para distinguir el cerramiento; no confirma un revoco ni su espesor. | Arquitectura; BIM · Arquitectura | El plano general de 2026-07-31 mantiene el edificio de oficinas de 200 m², mientras documentación anterior indica su supresión. Se conserva lo dibujado, pendiente de confirmación de la propiedad y del equipo de diseño.
Edificio de oficinas · Fábrica de bloques huecos de hormigón de 200 mm · eje A · tramo 25 | Planos de arquitectura del edificio de oficinas | Bloque hueco de hormigón de árido ligero | 0.9 × 0.2 × 1.1 | 285.95 | 287.05 | 0.198 | office_0089 | yes | 0.32072 | 0.918854 | 1.1 | 2.78 | 0.198 | office | Edificio de oficinas | {"name":"Bloque hueco de hormigón de árido ligero","source":"ARQ-OF-20260710 · Arquitectura A101 / p. 3, A103 / p. 5, A106 / p. 8; A301Cuadro de materiales ","status":"known"} | {"documented":[{"label":"Espesor del muro","value":0.2,"unit":"m","source":"ARQ-OF-20260710 · Arquitectura A101 / p. 3, A103 / p. 5, A106 / p. 8; A301Cuadro de materiales ","status":"documentado"}],"geometry":[{"label":"Dimensiones de la caja local del elemento (X, Y, Z)","value":"0.9 × 0.2 × 1.1","unit":"m","source":"Malla triangulada del elemento en ejes locales del edificio","status":"derivado"},{"label":"Cota mínima absoluta de la malla","value":285.95,"unit":"m","source":"Malla de proyecto y origen altimétrico 285 m","status":"derivado"},{"label":"Cota máxima absoluta de la malla","value":287.05,"unit":"m","source":"Malla de proyecto y origen altimétrico 285 m","status":"derivado"},{"label":"Volumen geométrico bruto","value":0.198,"unit":"m³","source":"Malla cerrada del elemento","status":"derivado"}],"notes":["Las dimensiones documentadas proceden de anotaciones o cuadros; la caja y el volumen se calculan a partir de la malla.","El volumen es exclusivamente geométrico y bruto; no representa una medición neta de material ni una cantidad de compra."]} | {"documentId":"ARQ-OF-20260710","title":"Planos de arquitectura del edificio de oficinas","date":"2026-07-10","sheet":"Arquitectura A101 / p. 3, A103 / p. 5, A106 / p. 8; A301Cuadro de materiales "} | ["El plano general de 2026-07-31 mantiene el edificio de oficinas de 200 m², mientras documentación anterior indica su supresión. Se conserva lo dibujado, pendiente de confirmación de la propiedad y del equipo de diseño.","Envolvente exterior controlada por la planta de arquitectura; no se han modelado individualmente todas las capas de acabado.","Registro de líneas del PDF general, envolvente de 20 × 10 m; eje local 1 al norte y acceso del lado A al oeste. Estimación de trabajo de implantación de ±0,15 m, pendiente de CAD; no constituye una precisión topográfica garantizada."] | {"horizontalStatus":"derivado","verticalStatus":"derivado","baseElevationM":285.95,"note":"Registro de líneas del PDF general, envolvente de 20 × 10 m; eje local 1 al norte y acceso del lado A al oeste. Estimación de trabajo de implantación de ±0,15 m, pendiente de CAD; no constituye una precisión topográfica garantizada."} | {"Pset_WallCommon":{"IsExternal":{"value":true,"source":"ARQ-OF-20260710 · A101, A103 y alzados; elemento de la envolvente exterior identificada en planta","status":"known"}}} | {"boundingBoxM":{"min":[16.119304,82.537972,0.95],"max":[16.440024,83.456826,2.05]},"extentsM":[0.32072,0.918854,1.1],"meshSurfaceM2":2.78,"meshVolumeM3":0.198,"closedSolid":true,"basis":"Geometría triangulada releída del IFC; envolventes y magnitudes no contractuales."} | {"material":true,"document":true,"quantities":true,"containerGuid":"3ztlotcerHPueDgxP84R6z","containerName":"Planta baja"} | {"id":"architecture","name":"Arquitectura"} | {"profileId":"block_masonry","name":"Fábrica de bloques · acabado mineral claro","materialName":"Bloque hueco de hormigón de árido ligero","physicalMaterialStatus":"known","physicalMaterialSource":"ARQ-OF-20260710 · Arquitectura A101 / p. 3, A103 / p. 5, A106 / p. 8; A301Cuadro de materiales ","appearanceStatus":"criterio_visual","appearanceBasis":"Bloque hueco documentado. Apariencia mineral clara para distinguir el cerramiento; no confirma un revoco ni su espesor.","note":"La apariencia gráfica no modifica ni confirma la especificación física del material."} | {"elementId":"office_0089","ifcGuid":"0HAyJttUbTXRfrMpI6BQLO","ifcClass":"IfcWall","buildingId":"office","buildingName":"Edificio de oficinas","sourceDocumentId":"ARQ-OF-20260710","sourceRepresentationKind":"documentary_mesh"} | {"layerId":"architecture","layerName":"Arquitectura","role":"Muro","basis":"Clasificación por función del elemento; no modifica las especificaciones documentales."} | architecture | {"profileId":"block_masonry","name":"Fábrica de bloques · acabado mineral claro","status":"criterio_visual","basis":"Bloque hueco documentado. Apariencia mineral clara para distinguir el cerramiento; no confirma un revoco ni su espesor.","physicalMaterialUnchanged":true} | ARQ-OF-20260710 · Arquitectura A101 / p. 3, A103 / p. 5, A106 / p. 8; A301Cuadro de materiales | Dimensiones contrastadas con los planos; reconstrucción geométrica a partir de documentación de diseño. | 0.2 | Muros segmentados con huecos reales para puertas y ventanas. | Envolvente exterior controlada por la planta de arquitectura; no se han modelado individualmente todas las capas de acabado. | Registro de líneas del PDF general, envolvente de 20 × 10 m; eje local 1 al norte y acceso del lado A al oeste. Estimación de trabajo de implantación de ±0,15 m, pendiente de CAD; no constituye una precisión topográfica garantizada. | Arquitectura | ARQ-OF-20260710 · Arquitectura A101 / p. 3, A103 / p. 5, A106 / p. 8; A301Cuadro de materiales | 285.95 | Arquitectura | Fábrica de bloques · acabado mineral claro | block_masonry | [0.843137,0.823529,0.772549] | 0.96 | 0 | Bloque hueco documentado. Apariencia mineral clara para distinguir el cerramiento; no confirma un revoco ni su espesor. | Arquitectura; BIM · Arquitectura | El plano general de 2026-07-31 mantiene el edificio de oficinas de 200 m², mientras documentación anterior indica su supresión. Se conserva lo dibujado, pendiente de confirmación de la propiedad y del equipo de diseño.
Edificio de oficinas · Fábrica de bloques huecos de hormigón de 200 mm · eje A · tramo 26 | Planos de arquitectura del edificio de oficinas | Bloque hueco de hormigón de árido ligero | 0.9 × 0.2 × 1.2 | 287.05 | 288.25 | 0.216 | office_0090 | yes | 0.32072 | 0.918854 | 1.2 | 3 | 0.216 | office | Edificio de oficinas | {"name":"Bloque hueco de hormigón de árido ligero","source":"ARQ-OF-20260710 · Arquitectura A101 / p. 3, A103 / p. 5, A106 / p. 8; A301Cuadro de materiales ","status":"known"} | {"documented":[{"label":"Espesor del muro","value":0.2,"unit":"m","source":"ARQ-OF-20260710 · Arquitectura A101 / p. 3, A103 / p. 5, A106 / p. 8; A301Cuadro de materiales ","status":"documentado"}],"geometry":[{"label":"Dimensiones de la caja local del elemento (X, Y, Z)","value":"0.9 × 0.2 × 1.2","unit":"m","source":"Malla triangulada del elemento en ejes locales del edificio","status":"derivado"},{"label":"Cota mínima absoluta de la malla","value":287.05,"unit":"m","source":"Malla de proyecto y origen altimétrico 285 m","status":"derivado"},{"label":"Cota máxima absoluta de la malla","value":288.25,"unit":"m","source":"Malla de proyecto y origen altimétrico 285 m","status":"derivado"},{"label":"Volumen geométrico bruto","value":0.216,"unit":"m³","source":"Malla cerrada del elemento","status":"derivado"}],"notes":["Las dimensiones documentadas proceden de anotaciones o cuadros; la caja y el volumen se calculan a partir de la malla.","El volumen es exclusivamente geométrico y bruto; no representa una medición neta de material ni una cantidad de compra."]} | {"documentId":"ARQ-OF-20260710","title":"Planos de arquitectura del edificio de oficinas","date":"2026-07-10","sheet":"Arquitectura A101 / p. 3, A103 / p. 5, A106 / p. 8; A301Cuadro de materiales "} | ["El plano general de 2026-07-31 mantiene el edificio de oficinas de 200 m², mientras documentación anterior indica su supresión. Se conserva lo dibujado, pendiente de confirmación de la propiedad y del equipo de diseño.","Envolvente exterior controlada por la planta de arquitectura; no se han modelado individualmente todas las capas de acabado.","Registro de líneas del PDF general, envolvente de 20 × 10 m; eje local 1 al norte y acceso del lado A al oeste. Estimación de trabajo de implantación de ±0,15 m, pendiente de CAD; no constituye una precisión topográfica garantizada."] | {"horizontalStatus":"derivado","verticalStatus":"derivado","baseElevationM":285.95,"note":"Registro de líneas del PDF general, envolvente de 20 × 10 m; eje local 1 al norte y acceso del lado A al oeste. Estimación de trabajo de implantación de ±0,15 m, pendiente de CAD; no constituye una precisión topográfica garantizada."} | {"Pset_WallCommon":{"IsExternal":{"value":true,"source":"ARQ-OF-20260710 · A101, A103 y alzados; elemento de la envolvente exterior identificada en planta","status":"known"}}} | {"boundingBoxM":{"min":[16.119304,82.537972,2.05],"max":[16.440024,83.456826,3.25]},"extentsM":[0.32072,0.918854,1.2],"meshSurfaceM2":3.0,"meshVolumeM3":0.216,"closedSolid":true,"basis":"Geometría triangulada releída del IFC; envolventes y magnitudes no contractuales."} | {"material":true,"document":true,"quantities":true,"containerGuid":"3ztlotcerHPueDgxP84R6z","containerName":"Planta baja"} | {"id":"architecture","name":"Arquitectura"} | {"profileId":"block_masonry","name":"Fábrica de bloques · acabado mineral claro","materialName":"Bloque hueco de hormigón de árido ligero","physicalMaterialStatus":"known","physicalMaterialSource":"ARQ-OF-20260710 · Arquitectura A101 / p. 3, A103 / p. 5, A106 / p. 8; A301Cuadro de materiales ","appearanceStatus":"criterio_visual","appearanceBasis":"Bloque hueco documentado. Apariencia mineral clara para distinguir el cerramiento; no confirma un revoco ni su espesor.","note":"La apariencia gráfica no modifica ni confirma la especificación física del material."} | {"elementId":"office_0090","ifcGuid":"0REanzld1JbOr$mp6rt7jO","ifcClass":"IfcWall","buildingId":"office","buildingName":"Edificio de oficinas","sourceDocumentId":"ARQ-OF-20260710","sourceRepresentationKind":"documentary_mesh"} | {"layerId":"architecture","layerName":"Arquitectura","role":"Muro","basis":"Clasificación por función del elemento; no modifica las especificaciones documentales."} | architecture | {"profileId":"block_masonry","name":"Fábrica de bloques · acabado mineral claro","status":"criterio_visual","basis":"Bloque hueco documentado. Apariencia mineral clara para distinguir el cerramiento; no confirma un revoco ni su espesor.","physicalMaterialUnchanged":true} | ARQ-OF-20260710 · Arquitectura A101 / p. 3, A103 / p. 5, A106 / p. 8; A301Cuadro de materiales | Dimensiones contrastadas con los planos; reconstrucción geométrica a partir de documentación de diseño. | 0.2 | Muros segmentados con huecos reales para puertas y ventanas. | Envolvente exterior controlada por la planta de arquitectura; no se han modelado individualmente todas las capas de acabado. | Registro de líneas del PDF general, envolvente de 20 × 10 m; eje local 1 al norte y acceso del lado A al oeste. Estimación de trabajo de implantación de ±0,15 m, pendiente de CAD; no constituye una precisión topográfica garantizada. | Arquitectura | ARQ-OF-20260710 · Arquitectura A101 / p. 3, A103 / p. 5, A106 / p. 8; A301Cuadro de materiales | 285.95 | Arquitectura | Fábrica de bloques · acabado mineral claro | block_masonry | [0.843137,0.823529,0.772549] | 0.96 | 0 | Bloque hueco documentado. Apariencia mineral clara para distinguir el cerramiento; no confirma un revoco ni su espesor. | Arquitectura; BIM · Arquitectura | El plano general de 2026-07-31 mantiene el edificio de oficinas de 200 m², mientras documentación anterior indica su supresión. Se conserva lo dibujado, pendiente de confirmación de la propiedad y del equipo de diseño.
Edificio de oficinas · Fábrica de bloques huecos de hormigón de 200 mm · eje A · tramo 27 | Planos de arquitectura del edificio de oficinas | Bloque hueco de hormigón de árido ligero | 0.9 × 0.2 × 1.1 | 288.25 | 289.35 | 0.198 | office_0091 | yes | 0.32072 | 0.918854 | 1.1 | 2.78 | 0.198 | office | Edificio de oficinas | {"name":"Bloque hueco de hormigón de árido ligero","source":"ARQ-OF-20260710 · Arquitectura A101 / p. 3, A103 / p. 5, A106 / p. 8; A301Cuadro de materiales ","status":"known"} | {"documented":[{"label":"Espesor del muro","value":0.2,"unit":"m","source":"ARQ-OF-20260710 · Arquitectura A101 / p. 3, A103 / p. 5, A106 / p. 8; A301Cuadro de materiales ","status":"documentado"}],"geometry":[{"label":"Dimensiones de la caja local del elemento (X, Y, Z)","value":"0.9 × 0.2 × 1.1","unit":"m","source":"Malla triangulada del elemento en ejes locales del edificio","status":"derivado"},{"label":"Cota mínima absoluta de la malla","value":288.25,"unit":"m","source":"Malla de proyecto y origen altimétrico 285 m","status":"derivado"},{"label":"Cota máxima absoluta de la malla","value":289.35,"unit":"m","source":"Malla de proyecto y origen altimétrico 285 m","status":"derivado"},{"label":"Volumen geométrico bruto","value":0.198,"unit":"m³","source":"Malla cerrada del elemento","status":"derivado"}],"notes":["Las dimensiones documentadas proceden de anotaciones o cuadros; la caja y el volumen se calculan a partir de la malla.","El volumen es exclusivamente geométrico y bruto; no representa una medición neta de material ni una cantidad de compra."]} | {"documentId":"ARQ-OF-20260710","title":"Planos de arquitectura del edificio de oficinas","date":"2026-07-10","sheet":"Arquitectura A101 / p. 3, A103 / p. 5, A106 / p. 8; A301Cuadro de materiales "} | ["El plano general de 2026-07-31 mantiene el edificio de oficinas de 200 m², mientras documentación anterior indica su supresión. Se conserva lo dibujado, pendiente de confirmación de la propiedad y del equipo de diseño.","Envolvente exterior controlada por la planta de arquitectura; no se han modelado individualmente todas las capas de acabado.","Registro de líneas del PDF general, envolvente de 20 × 10 m; eje local 1 al norte y acceso del lado A al oeste. Estimación de trabajo de implantación de ±0,15 m, pendiente de CAD; no constituye una precisión topográfica garantizada."] | {"horizontalStatus":"derivado","verticalStatus":"derivado","baseElevationM":285.95,"note":"Registro de líneas del PDF general, envolvente de 20 × 10 m; eje local 1 al norte y acceso del lado A al oeste. Estimación de trabajo de implantación de ±0,15 m, pendiente de CAD; no constituye una precisión topográfica garantizada."} | {"Pset_WallCommon":{"IsExternal":{"value":true,"source":"ARQ-OF-20260710 · A101, A103 y alzados; elemento de la envolvente exterior identificada en planta","status":"known"}}} | {"boundingBoxM":{"min":[16.119304,82.537972,3.25],"max":[16.440024,83.456826,4.35]},"extentsM":[0.32072,0.918854,1.1],"meshSurfaceM2":2.78,"meshVolumeM3":0.198,"closedSolid":true,"basis":"Geometría triangulada releída del IFC; envolventes y magnitudes no contractuales."} | {"material":true,"document":true,"quantities":true,"containerGuid":"3ztlotcerHPueDgxP84R6z","containerName":"Planta baja"} | {"id":"architecture","name":"Arquitectura"} | {"profileId":"block_masonry","name":"Fábrica de bloques · acabado mineral claro","materialName":"Bloque hueco de hormigón de árido ligero","physicalMaterialStatus":"known","physicalMaterialSource":"ARQ-OF-20260710 · Arquitectura A101 / p. 3, A103 / p. 5, A106 / p. 8; A301Cuadro de materiales ","appearanceStatus":"criterio_visual","appearanceBasis":"Bloque hueco documentado. Apariencia mineral clara para distinguir el cerramiento; no confirma un revoco ni su espesor.","note":"La apariencia gráfica no modifica ni confirma la especificación física del material."} | {"elementId":"office_0091","ifcGuid":"3SLzQMSEDRTBgc325HZO1D","ifcClass":"IfcWall","buildingId":"office","buildingName":"Edificio de oficinas","sourceDocumentId":"ARQ-OF-20260710","sourceRepresentationKind":"documentary_mesh"} | {"layerId":"architecture","layerName":"Arquitectura","role":"Muro","basis":"Clasificación por función del elemento; no modifica las especificaciones documentales."} | architecture | {"profileId":"block_masonry","name":"Fábrica de bloques · acabado mineral claro","status":"criterio_visual","basis":"Bloque hueco documentado. Apariencia mineral clara para distinguir el cerramiento; no confirma un revoco ni su espesor.","physicalMaterialUnchanged":true} | ARQ-OF-20260710 · Arquitectura A101 / p. 3, A103 / p. 5, A106 / p. 8; A301Cuadro de materiales | Dimensiones contrastadas con los planos; reconstrucción geométrica a partir de documentación de diseño. | 0.2 | Muros segmentados con huecos reales para puertas y ventanas. | Envolvente exterior controlada por la planta de arquitectura; no se han modelado individualmente todas las capas de acabado. | Registro de líneas del PDF general, envolvente de 20 × 10 m; eje local 1 al norte y acceso del lado A al oeste. Estimación de trabajo de implantación de ±0,15 m, pendiente de CAD; no constituye una precisión topográfica garantizada. | Arquitectura | ARQ-OF-20260710 · Arquitectura A101 / p. 3, A103 / p. 5, A106 / p. 8; A301Cuadro de materiales | 285.95 | Arquitectura | Fábrica de bloques · acabado mineral claro | block_masonry | [0.843137,0.823529,0.772549] | 0.96 | 0 | Bloque hueco documentado. Apariencia mineral clara para distinguir el cerramiento; no confirma un revoco ni su espesor. | Arquitectura; BIM · Arquitectura | El plano general de 2026-07-31 mantiene el edificio de oficinas de 200 m², mientras documentación anterior indica su supresión. Se conserva lo dibujado, pendiente de confirmación de la propiedad y del equipo de diseño.
Edificio de oficinas · Fábrica de bloques huecos de hormigón de 200 mm · eje A · tramo 28 | Planos de arquitectura del edificio de oficinas | Bloque hueco de hormigón de árido ligero | 0.9 × 0.2 × 1.6 | 289.35 | 290.95 | 0.288 | office_0092 | yes | 0.32072 | 0.918854 | 1.6 | 3.88 | 0.288 | office | Edificio de oficinas | {"name":"Bloque hueco de hormigón de árido ligero","source":"ARQ-OF-20260710 · Arquitectura A101 / p. 3, A103 / p. 5, A106 / p. 8; A301Cuadro de materiales ","status":"known"} | {"documented":[{"label":"Espesor del muro","value":0.2,"unit":"m","source":"ARQ-OF-20260710 · Arquitectura A101 / p. 3, A103 / p. 5, A106 / p. 8; A301Cuadro de materiales ","status":"documentado"}],"geometry":[{"label":"Dimensiones de la caja local del elemento (X, Y, Z)","value":"0.9 × 0.2 × 1.6","unit":"m","source":"Malla triangulada del elemento en ejes locales del edificio","status":"derivado"},{"label":"Cota mínima absoluta de la malla","value":289.35,"unit":"m","source":"Malla de proyecto y origen altimétrico 285 m","status":"derivado"},{"label":"Cota máxima absoluta de la malla","value":290.95,"unit":"m","source":"Malla de proyecto y origen altimétrico 285 m","status":"derivado"},{"label":"Volumen geométrico bruto","value":0.288,"unit":"m³","source":"Malla cerrada del elemento","status":"derivado"}],"notes":["Las dimensiones documentadas proceden de anotaciones o cuadros; la caja y el volumen se calculan a partir de la malla.","El volumen es exclusivamente geométrico y bruto; no representa una medición neta de material ni una cantidad de compra."]} | {"documentId":"ARQ-OF-20260710","title":"Planos de arquitectura del edificio de oficinas","date":"2026-07-10","sheet":"Arquitectura A101 / p. 3, A103 / p. 5, A106 / p. 8; A301Cuadro de materiales "} | ["El plano general de 2026-07-31 mantiene el edificio de oficinas de 200 m², mientras documentación anterior indica su supresión. Se conserva lo dibujado, pendiente de confirmación de la propiedad y del equipo de diseño.","Envolvente exterior controlada por la planta de arquitectura; no se han modelado individualmente todas las capas de acabado.","Registro de líneas del PDF general, envolvente de 20 × 10 m; eje local 1 al norte y acceso del lado A al oeste. Estimación de trabajo de implantación de ±0,15 m, pendiente de CAD; no constituye una precisión topográfica garantizada."] | {"horizontalStatus":"derivado","verticalStatus":"derivado","baseElevationM":285.95,"note":"Registro de líneas del PDF general, envolvente de 20 × 10 m; eje local 1 al norte y acceso del lado A al oeste. Estimación de trabajo de implantación de ±0,15 m, pendiente de CAD; no constituye una precisión topográfica garantizada."} | {"Pset_WallCommon":{"IsExternal":{"value":true,"source":"ARQ-OF-20260710 · A101, A103 y alzados; elemento de la envolvente exterior identificada en planta","status":"known"}}} | {"boundingBoxM":{"min":[16.119304,82.537972,4.35],"max":[16.440024,83.456826,5.95]},"extentsM":[0.32072,0.918854,1.6],"meshSurfaceM2":3.88,"meshVolumeM3":0.288,"closedSolid":true,"basis":"Geometría triangulada releída del IFC; envolventes y magnitudes no contractuales."} | {"material":true,"document":true,"quantities":true,"containerGuid":"3ztlotcerHPueDgxP84R6z","containerName":"Planta baja"} | {"id":"architecture","name":"Arquitectura"} | {"profileId":"block_masonry","name":"Fábrica de bloques · acabado mineral claro","materialName":"Bloque hueco de hormigón de árido ligero","physicalMaterialStatus":"known","physicalMaterialSource":"ARQ-OF-20260710 · Arquitectura A101 / p. 3, A103 / p. 5, A106 / p. 8; A301Cuadro de materiales ","appearanceStatus":"criterio_visual","appearanceBasis":"Bloque hueco documentado. Apariencia mineral clara para distinguir el cerramiento; no confirma un revoco ni su espesor.","note":"La apariencia gráfica no modifica ni confirma la especificación física del material."} | {"elementId":"office_0092","ifcGuid":"1qOspEPfvOweNJdICweQuR","ifcClass":"IfcWall","buildingId":"office","buildingName":"Edificio de oficinas","sourceDocumentId":"ARQ-OF-20260710","sourceRepresentationKind":"documentary_mesh"} | {"layerId":"architecture","layerName":"Arquitectura","role":"Muro","basis":"Clasificación por función del elemento; no modifica las especificaciones documentales."} | architecture | {"profileId":"block_masonry","name":"Fábrica de bloques · acabado mineral claro","status":"criterio_visual","basis":"Bloque hueco documentado. Apariencia mineral clara para distinguir el cerramiento; no confirma un revoco ni su espesor.","physicalMaterialUnchanged":true} | ARQ-OF-20260710 · Arquitectura A101 / p. 3, A103 / p. 5, A106 / p. 8; A301Cuadro de materiales | Dimensiones contrastadas con los planos; reconstrucción geométrica a partir de documentación de diseño. | 0.2 | Muros segmentados con huecos reales para puertas y ventanas. | Envolvente exterior controlada por la planta de arquitectura; no se han modelado individualmente todas las capas de acabado. | Registro de líneas del PDF general, envolvente de 20 × 10 m; eje local 1 al norte y acceso del lado A al oeste. Estimación de trabajo de implantación de ±0,15 m, pendiente de CAD; no constituye una precisión topográfica garantizada. | Arquitectura | ARQ-OF-20260710 · Arquitectura A101 / p. 3, A103 / p. 5, A106 / p. 8; A301Cuadro de materiales | 285.95 | Arquitectura | Fábrica de bloques · acabado mineral claro | block_masonry | [0.843137,0.823529,0.772549] | 0.96 | 0 | Bloque hueco documentado. Apariencia mineral clara para distinguir el cerramiento; no confirma un revoco ni su espesor. | Arquitectura; BIM · Arquitectura | El plano general de 2026-07-31 mantiene el edificio de oficinas de 200 m², mientras documentación anterior indica su supresión. Se conserva lo dibujado, pendiente de confirmación de la propiedad y del equipo de diseño.
Edificio de oficinas · Fábrica de bloques huecos de hormigón de 200 mm · eje A · tramo 29 | Planos de arquitectura del edificio de oficinas | Bloque hueco de hormigón de árido ligero | 0.9 × 0.2 × 1.1 | 285.95 | 287.05 | 0.198 | office_0093 | yes | 0.320719 | 0.918853 | 1.1 | 2.78 | 0.198 | office | Edificio de oficinas | {"name":"Bloque hueco de hormigón de árido ligero","source":"ARQ-OF-20260710 · Arquitectura A101 / p. 3, A103 / p. 5, A106 / p. 8; A301Cuadro de materiales ","status":"known"} | {"documented":[{"label":"Espesor del muro","value":0.2,"unit":"m","source":"ARQ-OF-20260710 · Arquitectura A101 / p. 3, A103 / p. 5, A106 / p. 8; A301Cuadro de materiales ","status":"documentado"}],"geometry":[{"label":"Dimensiones de la caja local del elemento (X, Y, Z)","value":"0.9 × 0.2 × 1.1","unit":"m","source":"Malla triangulada del elemento en ejes locales del edificio","status":"derivado"},{"label":"Cota mínima absoluta de la malla","value":285.95,"unit":"m","source":"Malla de proyecto y origen altimétrico 285 m","status":"derivado"},{"label":"Cota máxima absoluta de la malla","value":287.05,"unit":"m","source":"Malla de proyecto y origen altimétrico 285 m","status":"derivado"},{"label":"Volumen geométrico bruto","value":0.198,"unit":"m³","source":"Malla cerrada del elemento","status":"derivado"}],"notes":["Las dimensiones documentadas proceden de anotaciones o cuadros; la caja y el volumen se calculan a partir de la malla.","El volumen es exclusivamente geométrico y bruto; no representa una medición neta de material ni una cantidad de compra."]} | {"documentId":"ARQ-OF-20260710","title":"Planos de arquitectura del edificio de oficinas","date":"2026-07-10","sheet":"Arquitectura A101 / p. 3, A103 / p. 5, A106 / p. 8; A301Cuadro de materiales "} | ["El plano general de 2026-07-31 mantiene el edificio de oficinas de 200 m², mientras documentación anterior indica su supresión. Se conserva lo dibujado, pendiente de confirmación de la propiedad y del equipo de diseño.","Envolvente exterior controlada por la planta de arquitectura; no se han modelado individualmente todas las capas de acabado.","Registro de líneas del PDF general, envolvente de 20 × 10 m; eje local 1 al norte y acceso del lado A al oeste. Estimación de trabajo de implantación de ±0,15 m, pendiente de CAD; no constituye una precisión topográfica garantizada."] | {"horizontalStatus":"derivado","verticalStatus":"derivado","baseElevationM":285.95,"note":"Registro de líneas del PDF general, envolvente de 20 × 10 m; eje local 1 al norte y acceso del lado A al oeste. Estimación de trabajo de implantación de ±0,15 m, pendiente de CAD; no constituye una precisión topográfica garantizada."} | {"Pset_WallCommon":{"IsExternal":{"value":true,"source":"ARQ-OF-20260710 · A101, A103 y alzados; elemento de la envolvente exterior identificada en planta","status":"known"}}} | {"boundingBoxM":{"min":[15.996721,81.64636,0.95],"max":[16.31744,82.565213,2.05]},"extentsM":[0.320719,0.918853,1.1],"meshSurfaceM2":2.779997,"meshVolumeM3":0.198,"closedSolid":true,"basis":"Geometría triangulada releída del IFC; envolventes y magnitudes no contractuales."} | {"material":true,"document":true,"quantities":true,"containerGuid":"3ztlotcerHPueDgxP84R6z","containerName":"Planta baja"} | {"id":"architecture","name":"Arquitectura"} | {"profileId":"block_masonry","name":"Fábrica de bloques · acabado mineral claro","materialName":"Bloque hueco de hormigón de árido ligero","physicalMaterialStatus":"known","physicalMaterialSource":"ARQ-OF-20260710 · Arquitectura A101 / p. 3, A103 / p. 5, A106 / p. 8; A301Cuadro de materiales ","appearanceStatus":"criterio_visual","appearanceBasis":"Bloque hueco documentado. Apariencia mineral clara para distinguir el cerramiento; no confirma un revoco ni su espesor.","note":"La apariencia gráfica no modifica ni confirma la especificación física del material."} | {"elementId":"office_0093","ifcGuid":"0lXIevwYXRnxZ1S$8dhEKy","ifcClass":"IfcWall","buildingId":"office","buildingName":"Edificio de oficinas","sourceDocumentId":"ARQ-OF-20260710","sourceRepresentationKind":"documentary_mesh"} | {"layerId":"architecture","layerName":"Arquitectura","role":"Muro","basis":"Clasificación por función del elemento; no modifica las especificaciones documentales."} | architecture | {"profileId":"block_masonry","name":"Fábrica de bloques · acabado mineral claro","status":"criterio_visual","basis":"Bloque hueco documentado. Apariencia mineral clara para distinguir el cerramiento; no confirma un revoco ni su espesor.","physicalMaterialUnchanged":true} | ARQ-OF-20260710 · Arquitectura A101 / p. 3, A103 / p. 5, A106 / p. 8; A301Cuadro de materiales | Dimensiones contrastadas con los planos; reconstrucción geométrica a partir de documentación de diseño. | 0.2 | Muros segmentados con huecos reales para puertas y ventanas. | Envolvente exterior controlada por la planta de arquitectura; no se han modelado individualmente todas las capas de acabado. | Registro de líneas del PDF general, envolvente de 20 × 10 m; eje local 1 al norte y acceso del lado A al oeste. Estimación de trabajo de implantación de ±0,15 m, pendiente de CAD; no constituye una precisión topográfica garantizada. | Arquitectura | ARQ-OF-20260710 · Arquitectura A101 / p. 3, A103 / p. 5, A106 / p. 8; A301Cuadro de materiales | 285.95 | Arquitectura | Fábrica de bloques · acabado mineral claro | block_masonry | [0.843137,0.823529,0.772549] | 0.96 | 0 | Bloque hueco documentado. Apariencia mineral clara para distinguir el cerramiento; no confirma un revoco ni su espesor. | Arquitectura; BIM · Arquitectura | El plano general de 2026-07-31 mantiene el edificio de oficinas de 200 m², mientras documentación anterior indica su supresión. Se conserva lo dibujado, pendiente de confirmación de la propiedad y del equipo de diseño.
Edificio de oficinas · Fábrica de bloques huecos de hormigón de 200 mm · eje A · tramo 30 | Planos de arquitectura del edificio de oficinas | Bloque hueco de hormigón de árido ligero | 0.9 × 0.2 × 1.6 | 289.35 | 290.95 | 0.288 | office_0094 | yes | 0.320719 | 0.918853 | 1.6 | 3.88 | 0.288 | office | Edificio de oficinas | {"name":"Bloque hueco de hormigón de árido ligero","source":"ARQ-OF-20260710 · Arquitectura A101 / p. 3, A103 / p. 5, A106 / p. 8; A301Cuadro de materiales ","status":"known"} | {"documented":[{"label":"Espesor del muro","value":0.2,"unit":"m","source":"ARQ-OF-20260710 · Arquitectura A101 / p. 3, A103 / p. 5, A106 / p. 8; A301Cuadro de materiales ","status":"documentado"}],"geometry":[{"label":"Dimensiones de la caja local del elemento (X, Y, Z)","value":"0.9 × 0.2 × 1.6","unit":"m","source":"Malla triangulada del elemento en ejes locales del edificio","status":"derivado"},{"label":"Cota mínima absoluta de la malla","value":289.35,"unit":"m","source":"Malla de proyecto y origen altimétrico 285 m","status":"derivado"},{"label":"Cota máxima absoluta de la malla","value":290.95,"unit":"m","source":"Malla de proyecto y origen altimétrico 285 m","status":"derivado"},{"label":"Volumen geométrico bruto","value":0.288,"unit":"m³","source":"Malla cerrada del elemento","status":"derivado"}],"notes":["Las dimensiones documentadas proceden de anotaciones o cuadros; la caja y el volumen se calculan a partir de la malla.","El volumen es exclusivamente geométrico y bruto; no representa una medición neta de material ni una cantidad de compra."]} | {"documentId":"ARQ-OF-20260710","title":"Planos de arquitectura del edificio de oficinas","date":"2026-07-10","sheet":"Arquitectura A101 / p. 3, A103 / p. 5, A106 / p. 8; A301Cuadro de materiales "} | ["El plano general de 2026-07-31 mantiene el edificio de oficinas de 200 m², mientras documentación anterior indica su supresión. Se conserva lo dibujado, pendiente de confirmación de la propiedad y del equipo de diseño.","Envolvente exterior controlada por la planta de arquitectura; no se han modelado individualmente todas las capas de acabado.","Registro de líneas del PDF general, envolvente de 20 × 10 m; eje local 1 al norte y acceso del lado A al oeste. Estimación de trabajo de implantación de ±0,15 m, pendiente de CAD; no constituye una precisión topográfica garantizada."] | {"horizontalStatus":"derivado","verticalStatus":"derivado","baseElevationM":285.95,"note":"Registro de líneas del PDF general, envolvente de 20 × 10 m; eje local 1 al norte y acceso del lado A al oeste. Estimación de trabajo de implantación de ±0,15 m, pendiente de CAD; no constituye una precisión topográfica garantizada."} | {"Pset_WallCommon":{"IsExternal":{"value":true,"source":"ARQ-OF-20260710 · A101, A103 y alzados; elemento de la envolvente exterior identificada en planta","status":"known"}}} | {"boundingBoxM":{"min":[15.996721,81.64636,4.35],"max":[16.31744,82.565213,5.95]},"extentsM":[0.320719,0.918853,1.6],"meshSurfaceM2":3.879996,"meshVolumeM3":0.288,"closedSolid":true,"basis":"Geometría triangulada releída del IFC; envolventes y magnitudes no contractuales."} | {"material":true,"document":true,"quantities":true,"containerGuid":"3ztlotcerHPueDgxP84R6z","containerName":"Planta baja"} | {"id":"architecture","name":"Arquitectura"} | {"profileId":"block_masonry","name":"Fábrica de bloques · acabado mineral claro","materialName":"Bloque hueco de hormigón de árido ligero","physicalMaterialStatus":"known","physicalMaterialSource":"ARQ-OF-20260710 · Arquitectura A101 / p. 3, A103 / p. 5, A106 / p. 8; A301Cuadro de materiales ","appearanceStatus":"criterio_visual","appearanceBasis":"Bloque hueco documentado. Apariencia mineral clara para distinguir el cerramiento; no confirma un revoco ni su espesor.","note":"La apariencia gráfica no modifica ni confirma la especificación física del material."} | {"elementId":"office_0094","ifcGuid":"0j0DB9kffGmQ6BvZ7H5zfY","ifcClass":"IfcWall","buildingId":"office","buildingName":"Edificio de oficinas","sourceDocumentId":"ARQ-OF-20260710","sourceRepresentationKind":"documentary_mesh"} | {"layerId":"architecture","layerName":"Arquitectura","role":"Muro","basis":"Clasificación por función del elemento; no modifica las especificaciones documentales."} | architecture | {"profileId":"block_masonry","name":"Fábrica de bloques · acabado mineral claro","status":"criterio_visual","basis":"Bloque hueco documentado. Apariencia mineral clara para distinguir el cerramiento; no confirma un revoco ni su espesor.","physicalMaterialUnchanged":true} | ARQ-OF-20260710 · Arquitectura A101 / p. 3, A103 / p. 5, A106 / p. 8; A301Cuadro de materiales | Dimensiones contrastadas con los planos; reconstrucción geométrica a partir de documentación de diseño. | 0.2 | Muros segmentados con huecos reales para puertas y ventanas. | Envolvente exterior controlada por la planta de arquitectura; no se han modelado individualmente todas las capas de acabado. | Registro de líneas del PDF general, envolvente de 20 × 10 m; eje local 1 al norte y acceso del lado A al oeste. Estimación de trabajo de implantación de ±0,15 m, pendiente de CAD; no constituye una precisión topográfica garantizada. | Arquitectura | ARQ-OF-20260710 · Arquitectura A101 / p. 3, A103 / p. 5, A106 / p. 8; A301Cuadro de materiales | 285.95 | Arquitectura | Fábrica de bloques · acabado mineral claro | block_masonry | [0.843137,0.823529,0.772549] | 0.96 | 0 | Bloque hueco documentado. Apariencia mineral clara para distinguir el cerramiento; no confirma un revoco ni su espesor. | Arquitectura; BIM · Arquitectura | El plano general de 2026-07-31 mantiene el edificio de oficinas de 200 m², mientras documentación anterior indica su supresión. Se conserva lo dibujado, pendiente de confirmación de la propiedad y del equipo de diseño.
Edificio de oficinas · Fábrica de bloques huecos de hormigón de 200 mm · eje A · tramo 31 | Planos de arquitectura del edificio de oficinas | Bloque hueco de hormigón de árido ligero | 0.9 × 0.2 × 1.1 | 285.95 | 287.05 | 0.198 | office_0095 | yes | 0.32072 | 0.918854 | 1.1 | 2.78 | 0.198 | office | Edificio de oficinas | {"name":"Bloque hueco de hormigón de árido ligero","source":"ARQ-OF-20260710 · Arquitectura A101 / p. 3, A103 / p. 5, A106 / p. 8; A301Cuadro de materiales ","status":"known"} | {"documented":[{"label":"Espesor del muro","value":0.2,"unit":"m","source":"ARQ-OF-20260710 · Arquitectura A101 / p. 3, A103 / p. 5, A106 / p. 8; A301Cuadro de materiales ","status":"documentado"}],"geometry":[{"label":"Dimensiones de la caja local del elemento (X, Y, Z)","value":"0.9 × 0.2 × 1.1","unit":"m","source":"Malla triangulada del elemento en ejes locales del edificio","status":"derivado"},{"label":"Cota mínima absoluta de la malla","value":285.95,"unit":"m","source":"Malla de proyecto y origen altimétrico 285 m","status":"derivado"},{"label":"Cota máxima absoluta de la malla","value":287.05,"unit":"m","source":"Malla de proyecto y origen altimétrico 285 m","status":"derivado"},{"label":"Volumen geométrico bruto","value":0.198,"unit":"m³","source":"Malla cerrada del elemento","status":"derivado"}],"notes":["Las dimensiones documentadas proceden de anotaciones o cuadros; la caja y el volumen se calculan a partir de la malla.","El volumen es exclusivamente geométrico y bruto; no representa una medición neta de material ni una cantidad de compra."]} | {"documentId":"ARQ-OF-20260710","title":"Planos de arquitectura del edificio de oficinas","date":"2026-07-10","sheet":"Arquitectura A101 / p. 3, A103 / p. 5, A106 / p. 8; A301Cuadro de materiales "} | ["El plano general de 2026-07-31 mantiene el edificio de oficinas de 200 m², mientras documentación anterior indica su supresión. Se conserva lo dibujado, pendiente de confirmación de la propiedad y del equipo de diseño.","Envolvente exterior controlada por la planta de arquitectura; no se han modelado individualmente todas las capas de acabado.","Registro de líneas del PDF general, envolvente de 20 × 10 m; eje local 1 al norte y acceso del lado A al oeste. Estimación de trabajo de implantación de ±0,15 m, pendiente de CAD; no constituye una precisión topográfica garantizada."] | {"horizontalStatus":"derivado","verticalStatus":"derivado","baseElevationM":285.95,"note":"Registro de líneas del PDF general, envolvente de 20 × 10 m; eje local 1 al norte y acceso del lado A al oeste. Estimación de trabajo de implantación de ±0,15 m, pendiente de CAD; no constituye una precisión topográfica garantizada."} | {"Pset_WallCommon":{"IsExternal":{"value":true,"source":"ARQ-OF-20260710 · A101, A103 y alzados; elemento de la envolvente exterior identificada en planta","status":"known"}}} | {"boundingBoxM":{"min":[15.874137,80.754747,0.95],"max":[16.194857,81.673601,2.05]},"extentsM":[0.32072,0.918854,1.1],"meshSurfaceM2":2.78,"meshVolumeM3":0.198,"closedSolid":true,"basis":"Geometría triangulada releída del IFC; envolventes y magnitudes no contractuales."} | {"material":true,"document":true,"quantities":true,"containerGuid":"3ztlotcerHPueDgxP84R6z","containerName":"Planta baja"} | {"id":"architecture","name":"Arquitectura"} | {"profileId":"block_masonry","name":"Fábrica de bloques · acabado mineral claro","materialName":"Bloque hueco de hormigón de árido ligero","physicalMaterialStatus":"known","physicalMaterialSource":"ARQ-OF-20260710 · Arquitectura A101 / p. 3, A103 / p. 5, A106 / p. 8; A301Cuadro de materiales ","appearanceStatus":"criterio_visual","appearanceBasis":"Bloque hueco documentado. Apariencia mineral clara para distinguir el cerramiento; no confirma un revoco ni su espesor.","note":"La apariencia gráfica no modifica ni confirma la especificación física del material."} | {"elementId":"office_0095","ifcGuid":"0kRq4p3FvLTw1Kwe68fBqA","ifcClass":"IfcWall","buildingId":"office","buildingName":"Edificio de oficinas","sourceDocumentId":"ARQ-OF-20260710","sourceRepresentationKind":"documentary_mesh"} | {"layerId":"architecture","layerName":"Arquitectura","role":"Muro","basis":"Clasificación por función del elemento; no modifica las especificaciones documentales."} | architecture | {"profileId":"block_masonry","name":"Fábrica de bloques · acabado mineral claro","status":"criterio_visual","basis":"Bloque hueco documentado. Apariencia mineral clara para distinguir el cerramiento; no confirma un revoco ni su espesor.","physicalMaterialUnchanged":true} | ARQ-OF-20260710 · Arquitectura A101 / p. 3, A103 / p. 5, A106 / p. 8; A301Cuadro de materiales | Dimensiones contrastadas con los planos; reconstrucción geométrica a partir de documentación de diseño. | 0.2 | Muros segmentados con huecos reales para puertas y ventanas. | Envolvente exterior controlada por la planta de arquitectura; no se han modelado individualmente todas las capas de acabado. | Registro de líneas del PDF general, envolvente de 20 × 10 m; eje local 1 al norte y acceso del lado A al oeste. Estimación de trabajo de implantación de ±0,15 m, pendiente de CAD; no constituye una precisión topográfica garantizada. | Arquitectura | ARQ-OF-20260710 · Arquitectura A101 / p. 3, A103 / p. 5, A106 / p. 8; A301Cuadro de materiales | 285.95 | Arquitectura | Fábrica de bloques · acabado mineral claro | block_masonry | [0.843137,0.823529,0.772549] | 0.96 | 0 | Bloque hueco documentado. Apariencia mineral clara para distinguir el cerramiento; no confirma un revoco ni su espesor. | Arquitectura; BIM · Arquitectura | El plano general de 2026-07-31 mantiene el edificio de oficinas de 200 m², mientras documentación anterior indica su supresión. Se conserva lo dibujado, pendiente de confirmación de la propiedad y del equipo de diseño.
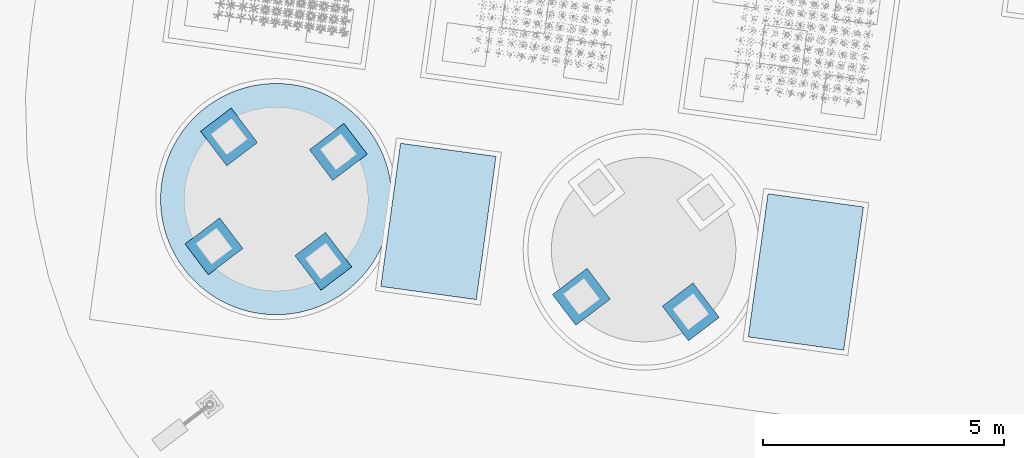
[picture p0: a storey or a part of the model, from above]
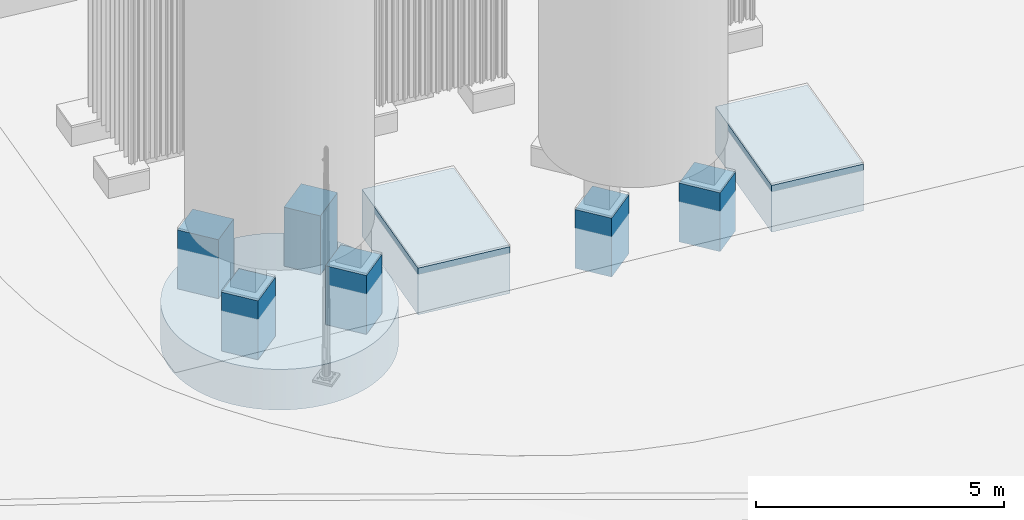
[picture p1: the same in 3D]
Properties of the parts of a building model (IFC4), part 120 of 134

# IfcWall (187)
Name | Document | Material = JH_Trazabilidad, Material = name | Dimensiones de la caja local del elemento (X, Y, Z) | Cota mínima absoluta de la malla (m) | Cota máxima absoluta de la malla (m) | Volumen geométrico bruto (m3) = Volumen geométrico (m³) | Reference = Identificador del elemento = Identificador | IsExternal | ExtensionX (m) | ExtensionY (m) | ExtensionZ (m) | SuperficieDeLaMalla (m2) | VolumenGeometrico (m3) = GrossVolume (m3) | buildingId | buildingName = Edificio | material | dimensions | JH_InformacionBIM, source = DocumentoFuente | issues = IncidenciasPendientes | positioning = PosicionYEstado | commonProperties | geometryMetrics | ifcAssociations | visualLayer | materialAppearance | visualizationIdentity | classification | layerId = IdentificadorCapa | appearance | Planos de referencia | Base geométrica | Espesor del muro (m) = Espesor del muro (m) | Tratamiento de los huecos | Representación de los acabados | Estado de la implantación | Disciplina | Referencia del material = JH_EvidenciaDeMaterial, source | Cota de planta baja terminada (m) | Capa BIM = NombreCapa | Acabado de visualización = Acabado | Perfil | ColorRGB | Rugosidad | Metallicidad | Referencia | Group | Discrepancia entre versiones
Edificio de oficinas · Fábrica de bloques huecos de hormigón de 200 mm · eje A · tramo 32 | Planos de arquitectura del edificio de oficinas | Bloque hueco de hormigón de árido ligero | 0.9 × 0.2 × 1.2 | 287.05 | 288.25 | 0.216 | office_0096 | yes | 0.32072 | 0.918854 | 1.2 | 3 | 0.216 | office | Edificio de oficinas | {"name":"Bloque hueco de hormigón de árido ligero","source":"ARQ-OF-20260710 · Arquitectura A101 / p. 3, A103 / p. 5, A106 / p. 8; A301Cuadro de materiales ","status":"known"} | {"documented":[{"label":"Espesor del muro","value":0.2,"unit":"m","source":"ARQ-OF-20260710 · Arquitectura A101 / p. 3, A103 / p. 5, A106 / p. 8; A301Cuadro de materiales ","status":"documentado"}],"geometry":[{"label":"Dimensiones de la caja local del elemento (X, Y, Z)","value":"0.9 × 0.2 × 1.2","unit":"m","source":"Malla triangulada del elemento en ejes locales del edificio","status":"derivado"},{"label":"Cota mínima absoluta de la malla","value":287.05,"unit":"m","source":"Malla de proyecto y origen altimétrico 285 m","status":"derivado"},{"label":"Cota máxima absoluta de la malla","value":288.25,"unit":"m","source":"Malla de proyecto y origen altimétrico 285 m","status":"derivado"},{"label":"Volumen geométrico bruto","value":0.216,"unit":"m³","source":"Malla cerrada del elemento","status":"derivado"}],"notes":["Las dimensiones documentadas proceden de anotaciones o cuadros; la caja y el volumen se calculan a partir de la malla.","El volumen es exclusivamente geométrico y bruto; no representa una medición neta de material ni una cantidad de compra."]} | {"documentId":"ARQ-OF-20260710","title":"Planos de arquitectura del edificio de oficinas","date":"2026-07-10","sheet":"Arquitectura A101 / p. 3, A103 / p. 5, A106 / p. 8; A301Cuadro de materiales "} | ["El plano general de 2026-07-31 mantiene el edificio de oficinas de 200 m², mientras documentación anterior indica su supresión. Se conserva lo dibujado, pendiente de confirmación de la propiedad y del equipo de diseño.","Envolvente exterior controlada por la planta de arquitectura; no se han modelado individualmente todas las capas de acabado.","Registro de líneas del PDF general, envolvente de 20 × 10 m; eje local 1 al norte y acceso del lado A al oeste. Estimación de trabajo de implantación de ±0,15 m, pendiente de CAD; no constituye una precisión topográfica garantizada."] | {"horizontalStatus":"derivado","verticalStatus":"derivado","baseElevationM":285.95,"note":"Registro de líneas del PDF general, envolvente de 20 × 10 m; eje local 1 al norte y acceso del lado A al oeste. Estimación de trabajo de implantación de ±0,15 m, pendiente de CAD; no constituye una precisión topográfica garantizada."} | {"Pset_WallCommon":{"IsExternal":{"value":true,"source":"ARQ-OF-20260710 · A101, A103 y alzados; elemento de la envolvente exterior identificada en planta","status":"known"}}} | {"boundingBoxM":{"min":[15.874137,80.754747,2.05],"max":[16.194857,81.673601,3.25]},"extentsM":[0.32072,0.918854,1.2],"meshSurfaceM2":3.0,"meshVolumeM3":0.216,"closedSolid":true,"basis":"Geometría triangulada releída del IFC; envolventes y magnitudes no contractuales."} | {"material":true,"document":true,"quantities":true,"containerGuid":"3ztlotcerHPueDgxP84R6z","containerName":"Planta baja"} | {"id":"architecture","name":"Arquitectura"} | {"profileId":"block_masonry","name":"Fábrica de bloques · acabado mineral claro","materialName":"Bloque hueco de hormigón de árido ligero","physicalMaterialStatus":"known","physicalMaterialSource":"ARQ-OF-20260710 · Arquitectura A101 / p. 3, A103 / p. 5, A106 / p. 8; A301Cuadro de materiales ","appearanceStatus":"criterio_visual","appearanceBasis":"Bloque hueco documentado. Apariencia mineral clara para distinguir el cerramiento; no confirma un revoco ni su espesor.","note":"La apariencia gráfica no modifica ni confirma la especificación física del material."} | {"elementId":"office_0096","ifcGuid":"2y80iJn$1H7fp1MscaRBGr","ifcClass":"IfcWall","buildingId":"office","buildingName":"Edificio de oficinas","sourceDocumentId":"ARQ-OF-20260710","sourceRepresentationKind":"documentary_mesh"} | {"layerId":"architecture","layerName":"Arquitectura","role":"Muro","basis":"Clasificación por función del elemento; no modifica las especificaciones documentales."} | architecture | {"profileId":"block_masonry","name":"Fábrica de bloques · acabado mineral claro","status":"criterio_visual","basis":"Bloque hueco documentado. Apariencia mineral clara para distinguir el cerramiento; no confirma un revoco ni su espesor.","physicalMaterialUnchanged":true} | ARQ-OF-20260710 · Arquitectura A101 / p. 3, A103 / p. 5, A106 / p. 8; A301Cuadro de materiales | Dimensiones contrastadas con los planos; reconstrucción geométrica a partir de documentación de diseño. | 0.2 | Muros segmentados con huecos reales para puertas y ventanas. | Envolvente exterior controlada por la planta de arquitectura; no se han modelado individualmente todas las capas de acabado. | Registro de líneas del PDF general, envolvente de 20 × 10 m; eje local 1 al norte y acceso del lado A al oeste. Estimación de trabajo de implantación de ±0,15 m, pendiente de CAD; no constituye una precisión topográfica garantizada. | Arquitectura | ARQ-OF-20260710 · Arquitectura A101 / p. 3, A103 / p. 5, A106 / p. 8; A301Cuadro de materiales | 285.95 | Arquitectura | Fábrica de bloques · acabado mineral claro | block_masonry | [0.843137,0.823529,0.772549] | 0.96 | 0 | Bloque hueco documentado. Apariencia mineral clara para distinguir el cerramiento; no confirma un revoco ni su espesor. | Arquitectura; BIM · Arquitectura | El plano general de 2026-07-31 mantiene el edificio de oficinas de 200 m², mientras documentación anterior indica su supresión. Se conserva lo dibujado, pendiente de confirmación de la propiedad y del equipo de diseño.
Edificio de oficinas · Fábrica de bloques huecos de hormigón de 200 mm · eje A · tramo 33 | Planos de arquitectura del edificio de oficinas | Bloque hueco de hormigón de árido ligero | 0.9 × 0.2 × 1.1 | 288.25 | 289.35 | 0.198 | office_0097 | yes | 0.32072 | 0.918854 | 1.1 | 2.78 | 0.198 | office | Edificio de oficinas | {"name":"Bloque hueco de hormigón de árido ligero","source":"ARQ-OF-20260710 · Arquitectura A101 / p. 3, A103 / p. 5, A106 / p. 8; A301Cuadro de materiales ","status":"known"} | {"documented":[{"label":"Espesor del muro","value":0.2,"unit":"m","source":"ARQ-OF-20260710 · Arquitectura A101 / p. 3, A103 / p. 5, A106 / p. 8; A301Cuadro de materiales ","status":"documentado"}],"geometry":[{"label":"Dimensiones de la caja local del elemento (X, Y, Z)","value":"0.9 × 0.2 × 1.1","unit":"m","source":"Malla triangulada del elemento en ejes locales del edificio","status":"derivado"},{"label":"Cota mínima absoluta de la malla","value":288.25,"unit":"m","source":"Malla de proyecto y origen altimétrico 285 m","status":"derivado"},{"label":"Cota máxima absoluta de la malla","value":289.35,"unit":"m","source":"Malla de proyecto y origen altimétrico 285 m","status":"derivado"},{"label":"Volumen geométrico bruto","value":0.198,"unit":"m³","source":"Malla cerrada del elemento","status":"derivado"}],"notes":["Las dimensiones documentadas proceden de anotaciones o cuadros; la caja y el volumen se calculan a partir de la malla.","El volumen es exclusivamente geométrico y bruto; no representa una medición neta de material ni una cantidad de compra."]} | {"documentId":"ARQ-OF-20260710","title":"Planos de arquitectura del edificio de oficinas","date":"2026-07-10","sheet":"Arquitectura A101 / p. 3, A103 / p. 5, A106 / p. 8; A301Cuadro de materiales "} | ["El plano general de 2026-07-31 mantiene el edificio de oficinas de 200 m², mientras documentación anterior indica su supresión. Se conserva lo dibujado, pendiente de confirmación de la propiedad y del equipo de diseño.","Envolvente exterior controlada por la planta de arquitectura; no se han modelado individualmente todas las capas de acabado.","Registro de líneas del PDF general, envolvente de 20 × 10 m; eje local 1 al norte y acceso del lado A al oeste. Estimación de trabajo de implantación de ±0,15 m, pendiente de CAD; no constituye una precisión topográfica garantizada."] | {"horizontalStatus":"derivado","verticalStatus":"derivado","baseElevationM":285.95,"note":"Registro de líneas del PDF general, envolvente de 20 × 10 m; eje local 1 al norte y acceso del lado A al oeste. Estimación de trabajo de implantación de ±0,15 m, pendiente de CAD; no constituye una precisión topográfica garantizada."} | {"Pset_WallCommon":{"IsExternal":{"value":true,"source":"ARQ-OF-20260710 · A101, A103 y alzados; elemento de la envolvente exterior identificada en planta","status":"known"}}} | {"boundingBoxM":{"min":[15.874137,80.754747,3.25],"max":[16.194857,81.673601,4.35]},"extentsM":[0.32072,0.918854,1.1],"meshSurfaceM2":2.78,"meshVolumeM3":0.198,"closedSolid":true,"basis":"Geometría triangulada releída del IFC; envolventes y magnitudes no contractuales."} | {"material":true,"document":true,"quantities":true,"containerGuid":"3ztlotcerHPueDgxP84R6z","containerName":"Planta baja"} | {"id":"architecture","name":"Arquitectura"} | {"profileId":"block_masonry","name":"Fábrica de bloques · acabado mineral claro","materialName":"Bloque hueco de hormigón de árido ligero","physicalMaterialStatus":"known","physicalMaterialSource":"ARQ-OF-20260710 · Arquitectura A101 / p. 3, A103 / p. 5, A106 / p. 8; A301Cuadro de materiales ","appearanceStatus":"criterio_visual","appearanceBasis":"Bloque hueco documentado. Apariencia mineral clara para distinguir el cerramiento; no confirma un revoco ni su espesor.","note":"La apariencia gráfica no modifica ni confirma la especificación física del material."} | {"elementId":"office_0097","ifcGuid":"2wbo7QfafL_RpiGlGNqqH7","ifcClass":"IfcWall","buildingId":"office","buildingName":"Edificio de oficinas","sourceDocumentId":"ARQ-OF-20260710","sourceRepresentationKind":"documentary_mesh"} | {"layerId":"architecture","layerName":"Arquitectura","role":"Muro","basis":"Clasificación por función del elemento; no modifica las especificaciones documentales."} | architecture | {"profileId":"block_masonry","name":"Fábrica de bloques · acabado mineral claro","status":"criterio_visual","basis":"Bloque hueco documentado. Apariencia mineral clara para distinguir el cerramiento; no confirma un revoco ni su espesor.","physicalMaterialUnchanged":true} | ARQ-OF-20260710 · Arquitectura A101 / p. 3, A103 / p. 5, A106 / p. 8; A301Cuadro de materiales | Dimensiones contrastadas con los planos; reconstrucción geométrica a partir de documentación de diseño. | 0.2 | Muros segmentados con huecos reales para puertas y ventanas. | Envolvente exterior controlada por la planta de arquitectura; no se han modelado individualmente todas las capas de acabado. | Registro de líneas del PDF general, envolvente de 20 × 10 m; eje local 1 al norte y acceso del lado A al oeste. Estimación de trabajo de implantación de ±0,15 m, pendiente de CAD; no constituye una precisión topográfica garantizada. | Arquitectura | ARQ-OF-20260710 · Arquitectura A101 / p. 3, A103 / p. 5, A106 / p. 8; A301Cuadro de materiales | 285.95 | Arquitectura | Fábrica de bloques · acabado mineral claro | block_masonry | [0.843137,0.823529,0.772549] | 0.96 | 0 | Bloque hueco documentado. Apariencia mineral clara para distinguir el cerramiento; no confirma un revoco ni su espesor. | Arquitectura; BIM · Arquitectura | El plano general de 2026-07-31 mantiene el edificio de oficinas de 200 m², mientras documentación anterior indica su supresión. Se conserva lo dibujado, pendiente de confirmación de la propiedad y del equipo de diseño.
Edificio de oficinas · Fábrica de bloques huecos de hormigón de 200 mm · eje A · tramo 34 | Planos de arquitectura del edificio de oficinas | Bloque hueco de hormigón de árido ligero | 0.9 × 0.2 × 1.6 | 289.35 | 290.95 | 0.288 | office_0098 | yes | 0.32072 | 0.918854 | 1.6 | 3.88 | 0.288 | office | Edificio de oficinas | {"name":"Bloque hueco de hormigón de árido ligero","source":"ARQ-OF-20260710 · Arquitectura A101 / p. 3, A103 / p. 5, A106 / p. 8; A301Cuadro de materiales ","status":"known"} | {"documented":[{"label":"Espesor del muro","value":0.2,"unit":"m","source":"ARQ-OF-20260710 · Arquitectura A101 / p. 3, A103 / p. 5, A106 / p. 8; A301Cuadro de materiales ","status":"documentado"}],"geometry":[{"label":"Dimensiones de la caja local del elemento (X, Y, Z)","value":"0.9 × 0.2 × 1.6","unit":"m","source":"Malla triangulada del elemento en ejes locales del edificio","status":"derivado"},{"label":"Cota mínima absoluta de la malla","value":289.35,"unit":"m","source":"Malla de proyecto y origen altimétrico 285 m","status":"derivado"},{"label":"Cota máxima absoluta de la malla","value":290.95,"unit":"m","source":"Malla de proyecto y origen altimétrico 285 m","status":"derivado"},{"label":"Volumen geométrico bruto","value":0.288,"unit":"m³","source":"Malla cerrada del elemento","status":"derivado"}],"notes":["Las dimensiones documentadas proceden de anotaciones o cuadros; la caja y el volumen se calculan a partir de la malla.","El volumen es exclusivamente geométrico y bruto; no representa una medición neta de material ni una cantidad de compra."]} | {"documentId":"ARQ-OF-20260710","title":"Planos de arquitectura del edificio de oficinas","date":"2026-07-10","sheet":"Arquitectura A101 / p. 3, A103 / p. 5, A106 / p. 8; A301Cuadro de materiales "} | ["El plano general de 2026-07-31 mantiene el edificio de oficinas de 200 m², mientras documentación anterior indica su supresión. Se conserva lo dibujado, pendiente de confirmación de la propiedad y del equipo de diseño.","Envolvente exterior controlada por la planta de arquitectura; no se han modelado individualmente todas las capas de acabado.","Registro de líneas del PDF general, envolvente de 20 × 10 m; eje local 1 al norte y acceso del lado A al oeste. Estimación de trabajo de implantación de ±0,15 m, pendiente de CAD; no constituye una precisión topográfica garantizada."] | {"horizontalStatus":"derivado","verticalStatus":"derivado","baseElevationM":285.95,"note":"Registro de líneas del PDF general, envolvente de 20 × 10 m; eje local 1 al norte y acceso del lado A al oeste. Estimación de trabajo de implantación de ±0,15 m, pendiente de CAD; no constituye una precisión topográfica garantizada."} | {"Pset_WallCommon":{"IsExternal":{"value":true,"source":"ARQ-OF-20260710 · A101, A103 y alzados; elemento de la envolvente exterior identificada en planta","status":"known"}}} | {"boundingBoxM":{"min":[15.874137,80.754747,4.35],"max":[16.194857,81.673601,5.95]},"extentsM":[0.32072,0.918854,1.6],"meshSurfaceM2":3.88,"meshVolumeM3":0.288,"closedSolid":true,"basis":"Geometría triangulada releída del IFC; envolventes y magnitudes no contractuales."} | {"material":true,"document":true,"quantities":true,"containerGuid":"3ztlotcerHPueDgxP84R6z","containerName":"Planta baja"} | {"id":"architecture","name":"Arquitectura"} | {"profileId":"block_masonry","name":"Fábrica de bloques · acabado mineral claro","materialName":"Bloque hueco de hormigón de árido ligero","physicalMaterialStatus":"known","physicalMaterialSource":"ARQ-OF-20260710 · Arquitectura A101 / p. 3, A103 / p. 5, A106 / p. 8; A301Cuadro de materiales ","appearanceStatus":"criterio_visual","appearanceBasis":"Bloque hueco documentado. Apariencia mineral clara para distinguir el cerramiento; no confirma un revoco ni su espesor.","note":"La apariencia gráfica no modifica ni confirma la especificación física del material."} | {"elementId":"office_0098","ifcGuid":"2vFBOGhazOUxqE4PhgUFa6","ifcClass":"IfcWall","buildingId":"office","buildingName":"Edificio de oficinas","sourceDocumentId":"ARQ-OF-20260710","sourceRepresentationKind":"documentary_mesh"} | {"layerId":"architecture","layerName":"Arquitectura","role":"Muro","basis":"Clasificación por función del elemento; no modifica las especificaciones documentales."} | architecture | {"profileId":"block_masonry","name":"Fábrica de bloques · acabado mineral claro","status":"criterio_visual","basis":"Bloque hueco documentado. Apariencia mineral clara para distinguir el cerramiento; no confirma un revoco ni su espesor.","physicalMaterialUnchanged":true} | ARQ-OF-20260710 · Arquitectura A101 / p. 3, A103 / p. 5, A106 / p. 8; A301Cuadro de materiales | Dimensiones contrastadas con los planos; reconstrucción geométrica a partir de documentación de diseño. | 0.2 | Muros segmentados con huecos reales para puertas y ventanas. | Envolvente exterior controlada por la planta de arquitectura; no se han modelado individualmente todas las capas de acabado. | Registro de líneas del PDF general, envolvente de 20 × 10 m; eje local 1 al norte y acceso del lado A al oeste. Estimación de trabajo de implantación de ±0,15 m, pendiente de CAD; no constituye una precisión topográfica garantizada. | Arquitectura | ARQ-OF-20260710 · Arquitectura A101 / p. 3, A103 / p. 5, A106 / p. 8; A301Cuadro de materiales | 285.95 | Arquitectura | Fábrica de bloques · acabado mineral claro | block_masonry | [0.843137,0.823529,0.772549] | 0.96 | 0 | Bloque hueco documentado. Apariencia mineral clara para distinguir el cerramiento; no confirma un revoco ni su espesor. | Arquitectura; BIM · Arquitectura | El plano general de 2026-07-31 mantiene el edificio de oficinas de 200 m², mientras documentación anterior indica su supresión. Se conserva lo dibujado, pendiente de confirmación de la propiedad y del equipo de diseño.
Edificio de oficinas · Fábrica de bloques huecos de hormigón de 200 mm · eje A · tramo 35 | Planos de arquitectura del edificio de oficinas | Bloque hueco de hormigón de árido ligero | 0.9 × 0.2 × 1.1 | 285.95 | 287.05 | 0.198 | office_0099 | yes | 0.320719 | 0.918854 | 1.1 | 2.78 | 0.198 | office | Edificio de oficinas | {"name":"Bloque hueco de hormigón de árido ligero","source":"ARQ-OF-20260710 · Arquitectura A101 / p. 3, A103 / p. 5, A106 / p. 8; A301Cuadro de materiales ","status":"known"} | {"documented":[{"label":"Espesor del muro","value":0.2,"unit":"m","source":"ARQ-OF-20260710 · Arquitectura A101 / p. 3, A103 / p. 5, A106 / p. 8; A301Cuadro de materiales ","status":"documentado"}],"geometry":[{"label":"Dimensiones de la caja local del elemento (X, Y, Z)","value":"0.9 × 0.2 × 1.1","unit":"m","source":"Malla triangulada del elemento en ejes locales del edificio","status":"derivado"},{"label":"Cota mínima absoluta de la malla","value":285.95,"unit":"m","source":"Malla de proyecto y origen altimétrico 285 m","status":"derivado"},{"label":"Cota máxima absoluta de la malla","value":287.05,"unit":"m","source":"Malla de proyecto y origen altimétrico 285 m","status":"derivado"},{"label":"Volumen geométrico bruto","value":0.198,"unit":"m³","source":"Malla cerrada del elemento","status":"derivado"}],"notes":["Las dimensiones documentadas proceden de anotaciones o cuadros; la caja y el volumen se calculan a partir de la malla.","El volumen es exclusivamente geométrico y bruto; no representa una medición neta de material ni una cantidad de compra."]} | {"documentId":"ARQ-OF-20260710","title":"Planos de arquitectura del edificio de oficinas","date":"2026-07-10","sheet":"Arquitectura A101 / p. 3, A103 / p. 5, A106 / p. 8; A301Cuadro de materiales "} | ["El plano general de 2026-07-31 mantiene el edificio de oficinas de 200 m², mientras documentación anterior indica su supresión. Se conserva lo dibujado, pendiente de confirmación de la propiedad y del equipo de diseño.","Envolvente exterior controlada por la planta de arquitectura; no se han modelado individualmente todas las capas de acabado.","Registro de líneas del PDF general, envolvente de 20 × 10 m; eje local 1 al norte y acceso del lado A al oeste. Estimación de trabajo de implantación de ±0,15 m, pendiente de CAD; no constituye una precisión topográfica garantizada."] | {"horizontalStatus":"derivado","verticalStatus":"derivado","baseElevationM":285.95,"note":"Registro de líneas del PDF general, envolvente de 20 × 10 m; eje local 1 al norte y acceso del lado A al oeste. Estimación de trabajo de implantación de ±0,15 m, pendiente de CAD; no constituye una precisión topográfica garantizada."} | {"Pset_WallCommon":{"IsExternal":{"value":true,"source":"ARQ-OF-20260710 · A101, A103 y alzados; elemento de la envolvente exterior identificada en planta","status":"known"}}} | {"boundingBoxM":{"min":[15.751554,79.863134,0.95],"max":[16.072273,80.781988,2.05]},"extentsM":[0.320719,0.918854,1.1],"meshSurfaceM2":2.78,"meshVolumeM3":0.198,"closedSolid":true,"basis":"Geometría triangulada releída del IFC; envolventes y magnitudes no contractuales."} | {"material":true,"document":true,"quantities":true,"containerGuid":"3ztlotcerHPueDgxP84R6z","containerName":"Planta baja"} | {"id":"architecture","name":"Arquitectura"} | {"profileId":"block_masonry","name":"Fábrica de bloques · acabado mineral claro","materialName":"Bloque hueco de hormigón de árido ligero","physicalMaterialStatus":"known","physicalMaterialSource":"ARQ-OF-20260710 · Arquitectura A101 / p. 3, A103 / p. 5, A106 / p. 8; A301Cuadro de materiales ","appearanceStatus":"criterio_visual","appearanceBasis":"Bloque hueco documentado. Apariencia mineral clara para distinguir el cerramiento; no confirma un revoco ni su espesor.","note":"La apariencia gráfica no modifica ni confirma la especificación física del material."} | {"elementId":"office_0099","ifcGuid":"1z4lniEcPSfRGt9myiJ9OH","ifcClass":"IfcWall","buildingId":"office","buildingName":"Edificio de oficinas","sourceDocumentId":"ARQ-OF-20260710","sourceRepresentationKind":"documentary_mesh"} | {"layerId":"architecture","layerName":"Arquitectura","role":"Muro","basis":"Clasificación por función del elemento; no modifica las especificaciones documentales."} | architecture | {"profileId":"block_masonry","name":"Fábrica de bloques · acabado mineral claro","status":"criterio_visual","basis":"Bloque hueco documentado. Apariencia mineral clara para distinguir el cerramiento; no confirma un revoco ni su espesor.","physicalMaterialUnchanged":true} | ARQ-OF-20260710 · Arquitectura A101 / p. 3, A103 / p. 5, A106 / p. 8; A301Cuadro de materiales | Dimensiones contrastadas con los planos; reconstrucción geométrica a partir de documentación de diseño. | 0.2 | Muros segmentados con huecos reales para puertas y ventanas. | Envolvente exterior controlada por la planta de arquitectura; no se han modelado individualmente todas las capas de acabado. | Registro de líneas del PDF general, envolvente de 20 × 10 m; eje local 1 al norte y acceso del lado A al oeste. Estimación de trabajo de implantación de ±0,15 m, pendiente de CAD; no constituye una precisión topográfica garantizada. | Arquitectura | ARQ-OF-20260710 · Arquitectura A101 / p. 3, A103 / p. 5, A106 / p. 8; A301Cuadro de materiales | 285.95 | Arquitectura | Fábrica de bloques · acabado mineral claro | block_masonry | [0.843137,0.823529,0.772549] | 0.96 | 0 | Bloque hueco documentado. Apariencia mineral clara para distinguir el cerramiento; no confirma un revoco ni su espesor. | Arquitectura; BIM · Arquitectura | El plano general de 2026-07-31 mantiene el edificio de oficinas de 200 m², mientras documentación anterior indica su supresión. Se conserva lo dibujado, pendiente de confirmación de la propiedad y del equipo de diseño.
Edificio de oficinas · Fábrica de bloques huecos de hormigón de 200 mm · eje A · tramo 36 | Planos de arquitectura del edificio de oficinas | Bloque hueco de hormigón de árido ligero | 0.9 × 0.2 × 1.6 | 289.35 | 290.95 | 0.288 | office_0100 | yes | 0.320719 | 0.918854 | 1.6 | 3.88 | 0.288 | office | Edificio de oficinas | {"name":"Bloque hueco de hormigón de árido ligero","source":"ARQ-OF-20260710 · Arquitectura A101 / p. 3, A103 / p. 5, A106 / p. 8; A301Cuadro de materiales ","status":"known"} | {"documented":[{"label":"Espesor del muro","value":0.2,"unit":"m","source":"ARQ-OF-20260710 · Arquitectura A101 / p. 3, A103 / p. 5, A106 / p. 8; A301Cuadro de materiales ","status":"documentado"}],"geometry":[{"label":"Dimensiones de la caja local del elemento (X, Y, Z)","value":"0.9 × 0.2 × 1.6","unit":"m","source":"Malla triangulada del elemento en ejes locales del edificio","status":"derivado"},{"label":"Cota mínima absoluta de la malla","value":289.35,"unit":"m","source":"Malla de proyecto y origen altimétrico 285 m","status":"derivado"},{"label":"Cota máxima absoluta de la malla","value":290.95,"unit":"m","source":"Malla de proyecto y origen altimétrico 285 m","status":"derivado"},{"label":"Volumen geométrico bruto","value":0.288,"unit":"m³","source":"Malla cerrada del elemento","status":"derivado"}],"notes":["Las dimensiones documentadas proceden de anotaciones o cuadros; la caja y el volumen se calculan a partir de la malla.","El volumen es exclusivamente geométrico y bruto; no representa una medición neta de material ni una cantidad de compra."]} | {"documentId":"ARQ-OF-20260710","title":"Planos de arquitectura del edificio de oficinas","date":"2026-07-10","sheet":"Arquitectura A101 / p. 3, A103 / p. 5, A106 / p. 8; A301Cuadro de materiales "} | ["El plano general de 2026-07-31 mantiene el edificio de oficinas de 200 m², mientras documentación anterior indica su supresión. Se conserva lo dibujado, pendiente de confirmación de la propiedad y del equipo de diseño.","Envolvente exterior controlada por la planta de arquitectura; no se han modelado individualmente todas las capas de acabado.","Registro de líneas del PDF general, envolvente de 20 × 10 m; eje local 1 al norte y acceso del lado A al oeste. Estimación de trabajo de implantación de ±0,15 m, pendiente de CAD; no constituye una precisión topográfica garantizada."] | {"horizontalStatus":"derivado","verticalStatus":"derivado","baseElevationM":285.95,"note":"Registro de líneas del PDF general, envolvente de 20 × 10 m; eje local 1 al norte y acceso del lado A al oeste. Estimación de trabajo de implantación de ±0,15 m, pendiente de CAD; no constituye una precisión topográfica garantizada."} | {"Pset_WallCommon":{"IsExternal":{"value":true,"source":"ARQ-OF-20260710 · A101, A103 y alzados; elemento de la envolvente exterior identificada en planta","status":"known"}}} | {"boundingBoxM":{"min":[15.751554,79.863134,4.35],"max":[16.072273,80.781988,5.95]},"extentsM":[0.320719,0.918854,1.6],"meshSurfaceM2":3.88,"meshVolumeM3":0.288,"closedSolid":true,"basis":"Geometría triangulada releída del IFC; envolventes y magnitudes no contractuales."} | {"material":true,"document":true,"quantities":true,"containerGuid":"3ztlotcerHPueDgxP84R6z","containerName":"Planta baja"} | {"id":"architecture","name":"Arquitectura"} | {"profileId":"block_masonry","name":"Fábrica de bloques · acabado mineral claro","materialName":"Bloque hueco de hormigón de árido ligero","physicalMaterialStatus":"known","physicalMaterialSource":"ARQ-OF-20260710 · Arquitectura A101 / p. 3, A103 / p. 5, A106 / p. 8; A301Cuadro de materiales ","appearanceStatus":"criterio_visual","appearanceBasis":"Bloque hueco documentado. Apariencia mineral clara para distinguir el cerramiento; no confirma un revoco ni su espesor.","note":"La apariencia gráfica no modifica ni confirma la especificación física del material."} | {"elementId":"office_0100","ifcGuid":"2AzJlG3W5OHuZYQNt9yHPI","ifcClass":"IfcWall","buildingId":"office","buildingName":"Edificio de oficinas","sourceDocumentId":"ARQ-OF-20260710","sourceRepresentationKind":"documentary_mesh"} | {"layerId":"architecture","layerName":"Arquitectura","role":"Muro","basis":"Clasificación por función del elemento; no modifica las especificaciones documentales."} | architecture | {"profileId":"block_masonry","name":"Fábrica de bloques · acabado mineral claro","status":"criterio_visual","basis":"Bloque hueco documentado. Apariencia mineral clara para distinguir el cerramiento; no confirma un revoco ni su espesor.","physicalMaterialUnchanged":true} | ARQ-OF-20260710 · Arquitectura A101 / p. 3, A103 / p. 5, A106 / p. 8; A301Cuadro de materiales | Dimensiones contrastadas con los planos; reconstrucción geométrica a partir de documentación de diseño. | 0.2 | Muros segmentados con huecos reales para puertas y ventanas. | Envolvente exterior controlada por la planta de arquitectura; no se han modelado individualmente todas las capas de acabado. | Registro de líneas del PDF general, envolvente de 20 × 10 m; eje local 1 al norte y acceso del lado A al oeste. Estimación de trabajo de implantación de ±0,15 m, pendiente de CAD; no constituye una precisión topográfica garantizada. | Arquitectura | ARQ-OF-20260710 · Arquitectura A101 / p. 3, A103 / p. 5, A106 / p. 8; A301Cuadro de materiales | 285.95 | Arquitectura | Fábrica de bloques · acabado mineral claro | block_masonry | [0.843137,0.823529,0.772549] | 0.96 | 0 | Bloque hueco documentado. Apariencia mineral clara para distinguir el cerramiento; no confirma un revoco ni su espesor. | Arquitectura; BIM · Arquitectura | El plano general de 2026-07-31 mantiene el edificio de oficinas de 200 m², mientras documentación anterior indica su supresión. Se conserva lo dibujado, pendiente de confirmación de la propiedad y del equipo de diseño.
Edificio de oficinas · Fábrica de bloques huecos de hormigón de 200 mm · eje A · tramo 37 | Planos de arquitectura del edificio de oficinas | Bloque hueco de hormigón de árido ligero | 0.9 × 0.2 × 1.1 | 285.95 | 287.05 | 0.198 | office_0101 | yes | 0.32072 | 0.918853 | 1.1 | 2.78 | 0.198 | office | Edificio de oficinas | {"name":"Bloque hueco de hormigón de árido ligero","source":"ARQ-OF-20260710 · Arquitectura A101 / p. 3, A103 / p. 5, A106 / p. 8; A301Cuadro de materiales ","status":"known"} | {"documented":[{"label":"Espesor del muro","value":0.2,"unit":"m","source":"ARQ-OF-20260710 · Arquitectura A101 / p. 3, A103 / p. 5, A106 / p. 8; A301Cuadro de materiales ","status":"documentado"}],"geometry":[{"label":"Dimensiones de la caja local del elemento (X, Y, Z)","value":"0.9 × 0.2 × 1.1","unit":"m","source":"Malla triangulada del elemento en ejes locales del edificio","status":"derivado"},{"label":"Cota mínima absoluta de la malla","value":285.95,"unit":"m","source":"Malla de proyecto y origen altimétrico 285 m","status":"derivado"},{"label":"Cota máxima absoluta de la malla","value":287.05,"unit":"m","source":"Malla de proyecto y origen altimétrico 285 m","status":"derivado"},{"label":"Volumen geométrico bruto","value":0.198,"unit":"m³","source":"Malla cerrada del elemento","status":"derivado"}],"notes":["Las dimensiones documentadas proceden de anotaciones o cuadros; la caja y el volumen se calculan a partir de la malla.","El volumen es exclusivamente geométrico y bruto; no representa una medición neta de material ni una cantidad de compra."]} | {"documentId":"ARQ-OF-20260710","title":"Planos de arquitectura del edificio de oficinas","date":"2026-07-10","sheet":"Arquitectura A101 / p. 3, A103 / p. 5, A106 / p. 8; A301Cuadro de materiales "} | ["El plano general de 2026-07-31 mantiene el edificio de oficinas de 200 m², mientras documentación anterior indica su supresión. Se conserva lo dibujado, pendiente de confirmación de la propiedad y del equipo de diseño.","Envolvente exterior controlada por la planta de arquitectura; no se han modelado individualmente todas las capas de acabado.","Registro de líneas del PDF general, envolvente de 20 × 10 m; eje local 1 al norte y acceso del lado A al oeste. Estimación de trabajo de implantación de ±0,15 m, pendiente de CAD; no constituye una precisión topográfica garantizada."] | {"horizontalStatus":"derivado","verticalStatus":"derivado","baseElevationM":285.95,"note":"Registro de líneas del PDF general, envolvente de 20 × 10 m; eje local 1 al norte y acceso del lado A al oeste. Estimación de trabajo de implantación de ±0,15 m, pendiente de CAD; no constituye una precisión topográfica garantizada."} | {"Pset_WallCommon":{"IsExternal":{"value":true,"source":"ARQ-OF-20260710 · A101, A103 y alzados; elemento de la envolvente exterior identificada en planta","status":"known"}}} | {"boundingBoxM":{"min":[15.62897,78.971522,0.95],"max":[15.94969,79.890375,2.05]},"extentsM":[0.32072,0.918853,1.1],"meshSurfaceM2":2.779999,"meshVolumeM3":0.198,"closedSolid":true,"basis":"Geometría triangulada releída del IFC; envolventes y magnitudes no contractuales."} | {"material":true,"document":true,"quantities":true,"containerGuid":"3ztlotcerHPueDgxP84R6z","containerName":"Planta baja"} | {"id":"architecture","name":"Arquitectura"} | {"profileId":"block_masonry","name":"Fábrica de bloques · acabado mineral claro","materialName":"Bloque hueco de hormigón de árido ligero","physicalMaterialStatus":"known","physicalMaterialSource":"ARQ-OF-20260710 · Arquitectura A101 / p. 3, A103 / p. 5, A106 / p. 8; A301Cuadro de materiales ","appearanceStatus":"criterio_visual","appearanceBasis":"Bloque hueco documentado. Apariencia mineral clara para distinguir el cerramiento; no confirma un revoco ni su espesor.","note":"La apariencia gráfica no modifica ni confirma la especificación física del material."} | {"elementId":"office_0101","ifcGuid":"2X7o99Z01Hz8SQ6uK_sgCC","ifcClass":"IfcWall","buildingId":"office","buildingName":"Edificio de oficinas","sourceDocumentId":"ARQ-OF-20260710","sourceRepresentationKind":"documentary_mesh"} | {"layerId":"architecture","layerName":"Arquitectura","role":"Muro","basis":"Clasificación por función del elemento; no modifica las especificaciones documentales."} | architecture | {"profileId":"block_masonry","name":"Fábrica de bloques · acabado mineral claro","status":"criterio_visual","basis":"Bloque hueco documentado. Apariencia mineral clara para distinguir el cerramiento; no confirma un revoco ni su espesor.","physicalMaterialUnchanged":true} | ARQ-OF-20260710 · Arquitectura A101 / p. 3, A103 / p. 5, A106 / p. 8; A301Cuadro de materiales | Dimensiones contrastadas con los planos; reconstrucción geométrica a partir de documentación de diseño. | 0.2 | Muros segmentados con huecos reales para puertas y ventanas. | Envolvente exterior controlada por la planta de arquitectura; no se han modelado individualmente todas las capas de acabado. | Registro de líneas del PDF general, envolvente de 20 × 10 m; eje local 1 al norte y acceso del lado A al oeste. Estimación de trabajo de implantación de ±0,15 m, pendiente de CAD; no constituye una precisión topográfica garantizada. | Arquitectura | ARQ-OF-20260710 · Arquitectura A101 / p. 3, A103 / p. 5, A106 / p. 8; A301Cuadro de materiales | 285.95 | Arquitectura | Fábrica de bloques · acabado mineral claro | block_masonry | [0.843137,0.823529,0.772549] | 0.96 | 0 | Bloque hueco documentado. Apariencia mineral clara para distinguir el cerramiento; no confirma un revoco ni su espesor. | Arquitectura; BIM · Arquitectura | El plano general de 2026-07-31 mantiene el edificio de oficinas de 200 m², mientras documentación anterior indica su supresión. Se conserva lo dibujado, pendiente de confirmación de la propiedad y del equipo de diseño.
Edificio de oficinas · Fábrica de bloques huecos de hormigón de 200 mm · eje A · tramo 38 | Planos de arquitectura del edificio de oficinas | Bloque hueco de hormigón de árido ligero | 0.9 × 0.2 × 1.2 | 287.05 | 288.25 | 0.216 | office_0102 | yes | 0.32072 | 0.918853 | 1.2 | 3 | 0.216 | office | Edificio de oficinas | {"name":"Bloque hueco de hormigón de árido ligero","source":"ARQ-OF-20260710 · Arquitectura A101 / p. 3, A103 / p. 5, A106 / p. 8; A301Cuadro de materiales ","status":"known"} | {"documented":[{"label":"Espesor del muro","value":0.2,"unit":"m","source":"ARQ-OF-20260710 · Arquitectura A101 / p. 3, A103 / p. 5, A106 / p. 8; A301Cuadro de materiales ","status":"documentado"}],"geometry":[{"label":"Dimensiones de la caja local del elemento (X, Y, Z)","value":"0.9 × 0.2 × 1.2","unit":"m","source":"Malla triangulada del elemento en ejes locales del edificio","status":"derivado"},{"label":"Cota mínima absoluta de la malla","value":287.05,"unit":"m","source":"Malla de proyecto y origen altimétrico 285 m","status":"derivado"},{"label":"Cota máxima absoluta de la malla","value":288.25,"unit":"m","source":"Malla de proyecto y origen altimétrico 285 m","status":"derivado"},{"label":"Volumen geométrico bruto","value":0.216,"unit":"m³","source":"Malla cerrada del elemento","status":"derivado"}],"notes":["Las dimensiones documentadas proceden de anotaciones o cuadros; la caja y el volumen se calculan a partir de la malla.","El volumen es exclusivamente geométrico y bruto; no representa una medición neta de material ni una cantidad de compra."]} | {"documentId":"ARQ-OF-20260710","title":"Planos de arquitectura del edificio de oficinas","date":"2026-07-10","sheet":"Arquitectura A101 / p. 3, A103 / p. 5, A106 / p. 8; A301Cuadro de materiales "} | ["El plano general de 2026-07-31 mantiene el edificio de oficinas de 200 m², mientras documentación anterior indica su supresión. Se conserva lo dibujado, pendiente de confirmación de la propiedad y del equipo de diseño.","Envolvente exterior controlada por la planta de arquitectura; no se han modelado individualmente todas las capas de acabado.","Registro de líneas del PDF general, envolvente de 20 × 10 m; eje local 1 al norte y acceso del lado A al oeste. Estimación de trabajo de implantación de ±0,15 m, pendiente de CAD; no constituye una precisión topográfica garantizada."] | {"horizontalStatus":"derivado","verticalStatus":"derivado","baseElevationM":285.95,"note":"Registro de líneas del PDF general, envolvente de 20 × 10 m; eje local 1 al norte y acceso del lado A al oeste. Estimación de trabajo de implantación de ±0,15 m, pendiente de CAD; no constituye una precisión topográfica garantizada."} | {"Pset_WallCommon":{"IsExternal":{"value":true,"source":"ARQ-OF-20260710 · A101, A103 y alzados; elemento de la envolvente exterior identificada en planta","status":"known"}}} | {"boundingBoxM":{"min":[15.62897,78.971522,2.05],"max":[15.94969,79.890375,3.25]},"extentsM":[0.32072,0.918853,1.2],"meshSurfaceM2":2.999999,"meshVolumeM3":0.216,"closedSolid":true,"basis":"Geometría triangulada releída del IFC; envolventes y magnitudes no contractuales."} | {"material":true,"document":true,"quantities":true,"containerGuid":"3ztlotcerHPueDgxP84R6z","containerName":"Planta baja"} | {"id":"architecture","name":"Arquitectura"} | {"profileId":"block_masonry","name":"Fábrica de bloques · acabado mineral claro","materialName":"Bloque hueco de hormigón de árido ligero","physicalMaterialStatus":"known","physicalMaterialSource":"ARQ-OF-20260710 · Arquitectura A101 / p. 3, A103 / p. 5, A106 / p. 8; A301Cuadro de materiales ","appearanceStatus":"criterio_visual","appearanceBasis":"Bloque hueco documentado. Apariencia mineral clara para distinguir el cerramiento; no confirma un revoco ni su espesor.","note":"La apariencia gráfica no modifica ni confirma la especificación física del material."} | {"elementId":"office_0102","ifcGuid":"1YKhQAvHLSFwfD5x_nktmX","ifcClass":"IfcWall","buildingId":"office","buildingName":"Edificio de oficinas","sourceDocumentId":"ARQ-OF-20260710","sourceRepresentationKind":"documentary_mesh"} | {"layerId":"architecture","layerName":"Arquitectura","role":"Muro","basis":"Clasificación por función del elemento; no modifica las especificaciones documentales."} | architecture | {"profileId":"block_masonry","name":"Fábrica de bloques · acabado mineral claro","status":"criterio_visual","basis":"Bloque hueco documentado. Apariencia mineral clara para distinguir el cerramiento; no confirma un revoco ni su espesor.","physicalMaterialUnchanged":true} | ARQ-OF-20260710 · Arquitectura A101 / p. 3, A103 / p. 5, A106 / p. 8; A301Cuadro de materiales | Dimensiones contrastadas con los planos; reconstrucción geométrica a partir de documentación de diseño. | 0.2 | Muros segmentados con huecos reales para puertas y ventanas. | Envolvente exterior controlada por la planta de arquitectura; no se han modelado individualmente todas las capas de acabado. | Registro de líneas del PDF general, envolvente de 20 × 10 m; eje local 1 al norte y acceso del lado A al oeste. Estimación de trabajo de implantación de ±0,15 m, pendiente de CAD; no constituye una precisión topográfica garantizada. | Arquitectura | ARQ-OF-20260710 · Arquitectura A101 / p. 3, A103 / p. 5, A106 / p. 8; A301Cuadro de materiales | 285.95 | Arquitectura | Fábrica de bloques · acabado mineral claro | block_masonry | [0.843137,0.823529,0.772549] | 0.96 | 0 | Bloque hueco documentado. Apariencia mineral clara para distinguir el cerramiento; no confirma un revoco ni su espesor. | Arquitectura; BIM · Arquitectura | El plano general de 2026-07-31 mantiene el edificio de oficinas de 200 m², mientras documentación anterior indica su supresión. Se conserva lo dibujado, pendiente de confirmación de la propiedad y del equipo de diseño.
Edificio de oficinas · Fábrica de bloques huecos de hormigón de 200 mm · eje A · tramo 39 | Planos de arquitectura del edificio de oficinas | Bloque hueco de hormigón de árido ligero | 0.9 × 0.2 × 1.1 | 288.25 | 289.35 | 0.198 | office_0103 | yes | 0.32072 | 0.918853 | 1.1 | 2.78 | 0.198 | office | Edificio de oficinas | {"name":"Bloque hueco de hormigón de árido ligero","source":"ARQ-OF-20260710 · Arquitectura A101 / p. 3, A103 / p. 5, A106 / p. 8; A301Cuadro de materiales ","status":"known"} | {"documented":[{"label":"Espesor del muro","value":0.2,"unit":"m","source":"ARQ-OF-20260710 · Arquitectura A101 / p. 3, A103 / p. 5, A106 / p. 8; A301Cuadro de materiales ","status":"documentado"}],"geometry":[{"label":"Dimensiones de la caja local del elemento (X, Y, Z)","value":"0.9 × 0.2 × 1.1","unit":"m","source":"Malla triangulada del elemento en ejes locales del edificio","status":"derivado"},{"label":"Cota mínima absoluta de la malla","value":288.25,"unit":"m","source":"Malla de proyecto y origen altimétrico 285 m","status":"derivado"},{"label":"Cota máxima absoluta de la malla","value":289.35,"unit":"m","source":"Malla de proyecto y origen altimétrico 285 m","status":"derivado"},{"label":"Volumen geométrico bruto","value":0.198,"unit":"m³","source":"Malla cerrada del elemento","status":"derivado"}],"notes":["Las dimensiones documentadas proceden de anotaciones o cuadros; la caja y el volumen se calculan a partir de la malla.","El volumen es exclusivamente geométrico y bruto; no representa una medición neta de material ni una cantidad de compra."]} | {"documentId":"ARQ-OF-20260710","title":"Planos de arquitectura del edificio de oficinas","date":"2026-07-10","sheet":"Arquitectura A101 / p. 3, A103 / p. 5, A106 / p. 8; A301Cuadro de materiales "} | ["El plano general de 2026-07-31 mantiene el edificio de oficinas de 200 m², mientras documentación anterior indica su supresión. Se conserva lo dibujado, pendiente de confirmación de la propiedad y del equipo de diseño.","Envolvente exterior controlada por la planta de arquitectura; no se han modelado individualmente todas las capas de acabado.","Registro de líneas del PDF general, envolvente de 20 × 10 m; eje local 1 al norte y acceso del lado A al oeste. Estimación de trabajo de implantación de ±0,15 m, pendiente de CAD; no constituye una precisión topográfica garantizada."] | {"horizontalStatus":"derivado","verticalStatus":"derivado","baseElevationM":285.95,"note":"Registro de líneas del PDF general, envolvente de 20 × 10 m; eje local 1 al norte y acceso del lado A al oeste. Estimación de trabajo de implantación de ±0,15 m, pendiente de CAD; no constituye una precisión topográfica garantizada."} | {"Pset_WallCommon":{"IsExternal":{"value":true,"source":"ARQ-OF-20260710 · A101, A103 y alzados; elemento de la envolvente exterior identificada en planta","status":"known"}}} | {"boundingBoxM":{"min":[15.62897,78.971522,3.25],"max":[15.94969,79.890375,4.35]},"extentsM":[0.32072,0.918853,1.1],"meshSurfaceM2":2.779999,"meshVolumeM3":0.198,"closedSolid":true,"basis":"Geometría triangulada releída del IFC; envolventes y magnitudes no contractuales."} | {"material":true,"document":true,"quantities":true,"containerGuid":"3ztlotcerHPueDgxP84R6z","containerName":"Planta baja"} | {"id":"architecture","name":"Arquitectura"} | {"profileId":"block_masonry","name":"Fábrica de bloques · acabado mineral claro","materialName":"Bloque hueco de hormigón de árido ligero","physicalMaterialStatus":"known","physicalMaterialSource":"ARQ-OF-20260710 · Arquitectura A101 / p. 3, A103 / p. 5, A106 / p. 8; A301Cuadro de materiales ","appearanceStatus":"criterio_visual","appearanceBasis":"Bloque hueco documentado. Apariencia mineral clara para distinguir el cerramiento; no confirma un revoco ni su espesor.","note":"La apariencia gráfica no modifica ni confirma la especificación física del material."} | {"elementId":"office_0103","ifcGuid":"2f0G8XgjfTxed78DGQ69Ze","ifcClass":"IfcWall","buildingId":"office","buildingName":"Edificio de oficinas","sourceDocumentId":"ARQ-OF-20260710","sourceRepresentationKind":"documentary_mesh"} | {"layerId":"architecture","layerName":"Arquitectura","role":"Muro","basis":"Clasificación por función del elemento; no modifica las especificaciones documentales."} | architecture | {"profileId":"block_masonry","name":"Fábrica de bloques · acabado mineral claro","status":"criterio_visual","basis":"Bloque hueco documentado. Apariencia mineral clara para distinguir el cerramiento; no confirma un revoco ni su espesor.","physicalMaterialUnchanged":true} | ARQ-OF-20260710 · Arquitectura A101 / p. 3, A103 / p. 5, A106 / p. 8; A301Cuadro de materiales | Dimensiones contrastadas con los planos; reconstrucción geométrica a partir de documentación de diseño. | 0.2 | Muros segmentados con huecos reales para puertas y ventanas. | Envolvente exterior controlada por la planta de arquitectura; no se han modelado individualmente todas las capas de acabado. | Registro de líneas del PDF general, envolvente de 20 × 10 m; eje local 1 al norte y acceso del lado A al oeste. Estimación de trabajo de implantación de ±0,15 m, pendiente de CAD; no constituye una precisión topográfica garantizada. | Arquitectura | ARQ-OF-20260710 · Arquitectura A101 / p. 3, A103 / p. 5, A106 / p. 8; A301Cuadro de materiales | 285.95 | Arquitectura | Fábrica de bloques · acabado mineral claro | block_masonry | [0.843137,0.823529,0.772549] | 0.96 | 0 | Bloque hueco documentado. Apariencia mineral clara para distinguir el cerramiento; no confirma un revoco ni su espesor. | Arquitectura; BIM · Arquitectura | El plano general de 2026-07-31 mantiene el edificio de oficinas de 200 m², mientras documentación anterior indica su supresión. Se conserva lo dibujado, pendiente de confirmación de la propiedad y del equipo de diseño.
Edificio de oficinas · Fábrica de bloques huecos de hormigón de 200 mm · eje A · tramo 40 | Planos de arquitectura del edificio de oficinas | Bloque hueco de hormigón de árido ligero | 0.9 × 0.2 × 1.6 | 289.35 | 290.95 | 0.288 | office_0104 | yes | 0.32072 | 0.918853 | 1.6 | 3.88 | 0.288 | office | Edificio de oficinas | {"name":"Bloque hueco de hormigón de árido ligero","source":"ARQ-OF-20260710 · Arquitectura A101 / p. 3, A103 / p. 5, A106 / p. 8; A301Cuadro de materiales ","status":"known"} | {"documented":[{"label":"Espesor del muro","value":0.2,"unit":"m","source":"ARQ-OF-20260710 · Arquitectura A101 / p. 3, A103 / p. 5, A106 / p. 8; A301Cuadro de materiales ","status":"documentado"}],"geometry":[{"label":"Dimensiones de la caja local del elemento (X, Y, Z)","value":"0.9 × 0.2 × 1.6","unit":"m","source":"Malla triangulada del elemento en ejes locales del edificio","status":"derivado"},{"label":"Cota mínima absoluta de la malla","value":289.35,"unit":"m","source":"Malla de proyecto y origen altimétrico 285 m","status":"derivado"},{"label":"Cota máxima absoluta de la malla","value":290.95,"unit":"m","source":"Malla de proyecto y origen altimétrico 285 m","status":"derivado"},{"label":"Volumen geométrico bruto","value":0.288,"unit":"m³","source":"Malla cerrada del elemento","status":"derivado"}],"notes":["Las dimensiones documentadas proceden de anotaciones o cuadros; la caja y el volumen se calculan a partir de la malla.","El volumen es exclusivamente geométrico y bruto; no representa una medición neta de material ni una cantidad de compra."]} | {"documentId":"ARQ-OF-20260710","title":"Planos de arquitectura del edificio de oficinas","date":"2026-07-10","sheet":"Arquitectura A101 / p. 3, A103 / p. 5, A106 / p. 8; A301Cuadro de materiales "} | ["El plano general de 2026-07-31 mantiene el edificio de oficinas de 200 m², mientras documentación anterior indica su supresión. Se conserva lo dibujado, pendiente de confirmación de la propiedad y del equipo de diseño.","Envolvente exterior controlada por la planta de arquitectura; no se han modelado individualmente todas las capas de acabado.","Registro de líneas del PDF general, envolvente de 20 × 10 m; eje local 1 al norte y acceso del lado A al oeste. Estimación de trabajo de implantación de ±0,15 m, pendiente de CAD; no constituye una precisión topográfica garantizada."] | {"horizontalStatus":"derivado","verticalStatus":"derivado","baseElevationM":285.95,"note":"Registro de líneas del PDF general, envolvente de 20 × 10 m; eje local 1 al norte y acceso del lado A al oeste. Estimación de trabajo de implantación de ±0,15 m, pendiente de CAD; no constituye una precisión topográfica garantizada."} | {"Pset_WallCommon":{"IsExternal":{"value":true,"source":"ARQ-OF-20260710 · A101, A103 y alzados; elemento de la envolvente exterior identificada en planta","status":"known"}}} | {"boundingBoxM":{"min":[15.62897,78.971522,4.35],"max":[15.94969,79.890375,5.95]},"extentsM":[0.32072,0.918853,1.6],"meshSurfaceM2":3.879998,"meshVolumeM3":0.288,"closedSolid":true,"basis":"Geometría triangulada releída del IFC; envolventes y magnitudes no contractuales."} | {"material":true,"document":true,"quantities":true,"containerGuid":"3ztlotcerHPueDgxP84R6z","containerName":"Planta baja"} | {"id":"architecture","name":"Arquitectura"} | {"profileId":"block_masonry","name":"Fábrica de bloques · acabado mineral claro","materialName":"Bloque hueco de hormigón de árido ligero","physicalMaterialStatus":"known","physicalMaterialSource":"ARQ-OF-20260710 · Arquitectura A101 / p. 3, A103 / p. 5, A106 / p. 8; A301Cuadro de materiales ","appearanceStatus":"criterio_visual","appearanceBasis":"Bloque hueco documentado. Apariencia mineral clara para distinguir el cerramiento; no confirma un revoco ni su espesor.","note":"La apariencia gráfica no modifica ni confirma la especificación física del material."} | {"elementId":"office_0104","ifcGuid":"1DC0RovZHIJP7e09ZkPLzx","ifcClass":"IfcWall","buildingId":"office","buildingName":"Edificio de oficinas","sourceDocumentId":"ARQ-OF-20260710","sourceRepresentationKind":"documentary_mesh"} | {"layerId":"architecture","layerName":"Arquitectura","role":"Muro","basis":"Clasificación por función del elemento; no modifica las especificaciones documentales."} | architecture | {"profileId":"block_masonry","name":"Fábrica de bloques · acabado mineral claro","status":"criterio_visual","basis":"Bloque hueco documentado. Apariencia mineral clara para distinguir el cerramiento; no confirma un revoco ni su espesor.","physicalMaterialUnchanged":true} | ARQ-OF-20260710 · Arquitectura A101 / p. 3, A103 / p. 5, A106 / p. 8; A301Cuadro de materiales | Dimensiones contrastadas con los planos; reconstrucción geométrica a partir de documentación de diseño. | 0.2 | Muros segmentados con huecos reales para puertas y ventanas. | Envolvente exterior controlada por la planta de arquitectura; no se han modelado individualmente todas las capas de acabado. | Registro de líneas del PDF general, envolvente de 20 × 10 m; eje local 1 al norte y acceso del lado A al oeste. Estimación de trabajo de implantación de ±0,15 m, pendiente de CAD; no constituye una precisión topográfica garantizada. | Arquitectura | ARQ-OF-20260710 · Arquitectura A101 / p. 3, A103 / p. 5, A106 / p. 8; A301Cuadro de materiales | 285.95 | Arquitectura | Fábrica de bloques · acabado mineral claro | block_masonry | [0.843137,0.823529,0.772549] | 0.96 | 0 | Bloque hueco documentado. Apariencia mineral clara para distinguir el cerramiento; no confirma un revoco ni su espesor. | Arquitectura; BIM · Arquitectura | El plano general de 2026-07-31 mantiene el edificio de oficinas de 200 m², mientras documentación anterior indica su supresión. Se conserva lo dibujado, pendiente de confirmación de la propiedad y del equipo de diseño.
Edificio de oficinas · Fábrica de bloques huecos de hormigón de 200 mm · eje A · tramo 41 | Planos de arquitectura del edificio de oficinas | Bloque hueco de hormigón de árido ligero | 0.9 × 0.2 × 1.1 | 285.95 | 287.05 | 0.198 | office_0105 | yes | 0.32072 | 0.918853 | 1.1 | 2.78 | 0.198 | office | Edificio de oficinas | {"name":"Bloque hueco de hormigón de árido ligero","source":"ARQ-OF-20260710 · Arquitectura A101 / p. 3, A103 / p. 5, A106 / p. 8; A301Cuadro de materiales ","status":"known"} | {"documented":[{"label":"Espesor del muro","value":0.2,"unit":"m","source":"ARQ-OF-20260710 · Arquitectura A101 / p. 3, A103 / p. 5, A106 / p. 8; A301Cuadro de materiales ","status":"documentado"}],"geometry":[{"label":"Dimensiones de la caja local del elemento (X, Y, Z)","value":"0.9 × 0.2 × 1.1","unit":"m","source":"Malla triangulada del elemento en ejes locales del edificio","status":"derivado"},{"label":"Cota mínima absoluta de la malla","value":285.95,"unit":"m","source":"Malla de proyecto y origen altimétrico 285 m","status":"derivado"},{"label":"Cota máxima absoluta de la malla","value":287.05,"unit":"m","source":"Malla de proyecto y origen altimétrico 285 m","status":"derivado"},{"label":"Volumen geométrico bruto","value":0.198,"unit":"m³","source":"Malla cerrada del elemento","status":"derivado"}],"notes":["Las dimensiones documentadas proceden de anotaciones o cuadros; la caja y el volumen se calculan a partir de la malla.","El volumen es exclusivamente geométrico y bruto; no representa una medición neta de material ni una cantidad de compra."]} | {"documentId":"ARQ-OF-20260710","title":"Planos de arquitectura del edificio de oficinas","date":"2026-07-10","sheet":"Arquitectura A101 / p. 3, A103 / p. 5, A106 / p. 8; A301Cuadro de materiales "} | ["El plano general de 2026-07-31 mantiene el edificio de oficinas de 200 m², mientras documentación anterior indica su supresión. Se conserva lo dibujado, pendiente de confirmación de la propiedad y del equipo de diseño.","Envolvente exterior controlada por la planta de arquitectura; no se han modelado individualmente todas las capas de acabado.","Registro de líneas del PDF general, envolvente de 20 × 10 m; eje local 1 al norte y acceso del lado A al oeste. Estimación de trabajo de implantación de ±0,15 m, pendiente de CAD; no constituye una precisión topográfica garantizada."] | {"horizontalStatus":"derivado","verticalStatus":"derivado","baseElevationM":285.95,"note":"Registro de líneas del PDF general, envolvente de 20 × 10 m; eje local 1 al norte y acceso del lado A al oeste. Estimación de trabajo de implantación de ±0,15 m, pendiente de CAD; no constituye una precisión topográfica garantizada."} | {"Pset_WallCommon":{"IsExternal":{"value":true,"source":"ARQ-OF-20260710 · A101, A103 y alzados; elemento de la envolvente exterior identificada en planta","status":"known"}}} | {"boundingBoxM":{"min":[15.506386,78.079909,0.95],"max":[15.827106,78.998762,2.05]},"extentsM":[0.32072,0.918853,1.1],"meshSurfaceM2":2.780001,"meshVolumeM3":0.198,"closedSolid":true,"basis":"Geometría triangulada releída del IFC; envolventes y magnitudes no contractuales."} | {"material":true,"document":true,"quantities":true,"containerGuid":"3ztlotcerHPueDgxP84R6z","containerName":"Planta baja"} | {"id":"architecture","name":"Arquitectura"} | {"profileId":"block_masonry","name":"Fábrica de bloques · acabado mineral claro","materialName":"Bloque hueco de hormigón de árido ligero","physicalMaterialStatus":"known","physicalMaterialSource":"ARQ-OF-20260710 · Arquitectura A101 / p. 3, A103 / p. 5, A106 / p. 8; A301Cuadro de materiales ","appearanceStatus":"criterio_visual","appearanceBasis":"Bloque hueco documentado. Apariencia mineral clara para distinguir el cerramiento; no confirma un revoco ni su espesor.","note":"La apariencia gráfica no modifica ni confirma la especificación física del material."} | {"elementId":"office_0105","ifcGuid":"3Bk3L0sNbVeuwhzoiWP8Og","ifcClass":"IfcWall","buildingId":"office","buildingName":"Edificio de oficinas","sourceDocumentId":"ARQ-OF-20260710","sourceRepresentationKind":"documentary_mesh"} | {"layerId":"architecture","layerName":"Arquitectura","role":"Muro","basis":"Clasificación por función del elemento; no modifica las especificaciones documentales."} | architecture | {"profileId":"block_masonry","name":"Fábrica de bloques · acabado mineral claro","status":"criterio_visual","basis":"Bloque hueco documentado. Apariencia mineral clara para distinguir el cerramiento; no confirma un revoco ni su espesor.","physicalMaterialUnchanged":true} | ARQ-OF-20260710 · Arquitectura A101 / p. 3, A103 / p. 5, A106 / p. 8; A301Cuadro de materiales | Dimensiones contrastadas con los planos; reconstrucción geométrica a partir de documentación de diseño. | 0.2 | Muros segmentados con huecos reales para puertas y ventanas. | Envolvente exterior controlada por la planta de arquitectura; no se han modelado individualmente todas las capas de acabado. | Registro de líneas del PDF general, envolvente de 20 × 10 m; eje local 1 al norte y acceso del lado A al oeste. Estimación de trabajo de implantación de ±0,15 m, pendiente de CAD; no constituye una precisión topográfica garantizada. | Arquitectura | ARQ-OF-20260710 · Arquitectura A101 / p. 3, A103 / p. 5, A106 / p. 8; A301Cuadro de materiales | 285.95 | Arquitectura | Fábrica de bloques · acabado mineral claro | block_masonry | [0.843137,0.823529,0.772549] | 0.96 | 0 | Bloque hueco documentado. Apariencia mineral clara para distinguir el cerramiento; no confirma un revoco ni su espesor. | Arquitectura; BIM · Arquitectura | El plano general de 2026-07-31 mantiene el edificio de oficinas de 200 m², mientras documentación anterior indica su supresión. Se conserva lo dibujado, pendiente de confirmación de la propiedad y del equipo de diseño.
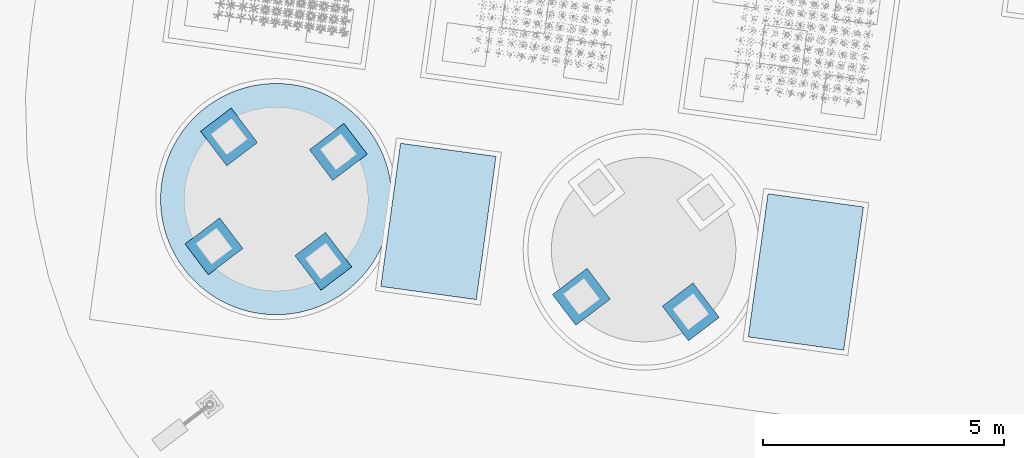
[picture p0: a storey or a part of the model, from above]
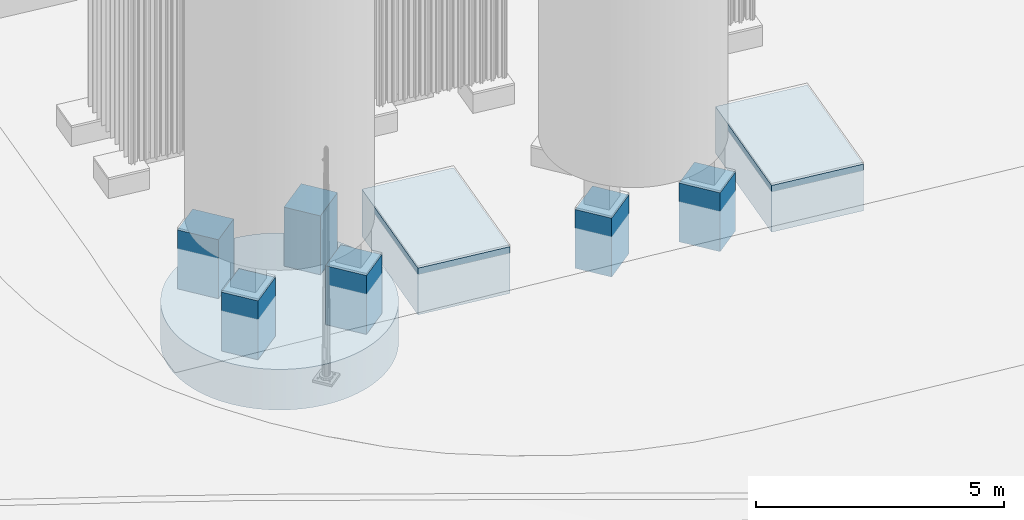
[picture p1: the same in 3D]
Properties of the parts of a building model (IFC4), part 122 of 134

# IfcWall (187)
Name | Document | Material = JH_Trazabilidad, Material = name | Dimensiones de la caja local del elemento (X, Y, Z) | Cota mínima absoluta de la malla (m) | Cota máxima absoluta de la malla (m) | Volumen geométrico bruto (m3) = Volumen geométrico (m³) | Reference = Identificador del elemento = Identificador | IsExternal | ExtensionX (m) | ExtensionY (m) | ExtensionZ (m) | SuperficieDeLaMalla (m2) | VolumenGeometrico (m3) = GrossVolume (m3) | buildingId | buildingName = Edificio | material | dimensions | JH_InformacionBIM, source = DocumentoFuente | issues = IncidenciasPendientes | positioning = PosicionYEstado | commonProperties | geometryMetrics | ifcAssociations | visualLayer | materialAppearance | visualizationIdentity | classification | layerId = IdentificadorCapa | appearance | Planos de referencia | Base geométrica | Espesor del muro (m) = Espesor del muro (m) | Tratamiento de los huecos | Representación de los acabados | Estado de la implantación | Disciplina | Referencia del material = JH_EvidenciaDeMaterial, source | Cota de planta baja terminada (m) | Capa BIM = NombreCapa | Acabado de visualización = Acabado | Perfil | ColorRGB | Rugosidad | Metallicidad | Referencia | Group | Discrepancia entre versiones
Edificio de oficinas · Fábrica de bloques huecos de hormigón de 200 mm · eje A · tramo 52 | Planos de arquitectura del edificio de oficinas | Bloque hueco de hormigón de árido ligero | 0.9 × 0.2 × 1.6 | 289.35 | 290.95 | 0.288 | office_0116 | yes | 0.32072 | 0.918853 | 1.6 | 3.88 | 0.288 | office | Edificio de oficinas | {"name":"Bloque hueco de hormigón de árido ligero","source":"ARQ-OF-20260710 · Arquitectura A101 / p. 3, A103 / p. 5, A106 / p. 8; A301Cuadro de materiales ","status":"known"} | {"documented":[{"label":"Espesor del muro","value":0.2,"unit":"m","source":"ARQ-OF-20260710 · Arquitectura A101 / p. 3, A103 / p. 5, A106 / p. 8; A301Cuadro de materiales ","status":"documentado"}],"geometry":[{"label":"Dimensiones de la caja local del elemento (X, Y, Z)","value":"0.9 × 0.2 × 1.6","unit":"m","source":"Malla triangulada del elemento en ejes locales del edificio","status":"derivado"},{"label":"Cota mínima absoluta de la malla","value":289.35,"unit":"m","source":"Malla de proyecto y origen altimétrico 285 m","status":"derivado"},{"label":"Cota máxima absoluta de la malla","value":290.95,"unit":"m","source":"Malla de proyecto y origen altimétrico 285 m","status":"derivado"},{"label":"Volumen geométrico bruto","value":0.288,"unit":"m³","source":"Malla cerrada del elemento","status":"derivado"}],"notes":["Las dimensiones documentadas proceden de anotaciones o cuadros; la caja y el volumen se calculan a partir de la malla.","El volumen es exclusivamente geométrico y bruto; no representa una medición neta de material ni una cantidad de compra."]} | {"documentId":"ARQ-OF-20260710","title":"Planos de arquitectura del edificio de oficinas","date":"2026-07-10","sheet":"Arquitectura A101 / p. 3, A103 / p. 5, A106 / p. 8; A301Cuadro de materiales "} | ["El plano general de 2026-07-31 mantiene el edificio de oficinas de 200 m², mientras documentación anterior indica su supresión. Se conserva lo dibujado, pendiente de confirmación de la propiedad y del equipo de diseño.","Envolvente exterior controlada por la planta de arquitectura; no se han modelado individualmente todas las capas de acabado.","Registro de líneas del PDF general, envolvente de 20 × 10 m; eje local 1 al norte y acceso del lado A al oeste. Estimación de trabajo de implantación de ±0,15 m, pendiente de CAD; no constituye una precisión topográfica garantizada."] | {"horizontalStatus":"derivado","verticalStatus":"derivado","baseElevationM":285.95,"note":"Registro de líneas del PDF general, envolvente de 20 × 10 m; eje local 1 al norte y acceso del lado A al oeste. Estimación de trabajo de implantación de ±0,15 m, pendiente de CAD; no constituye una precisión topográfica garantizada."} | {"Pset_WallCommon":{"IsExternal":{"value":true,"source":"ARQ-OF-20260710 · A101, A103 y alzados; elemento de la envolvente exterior identificada en planta","status":"known"}}} | {"boundingBoxM":{"min":[15.138636,75.405071,4.35],"max":[15.459356,76.323924,5.95]},"extentsM":[0.32072,0.918853,1.6],"meshSurfaceM2":3.880001,"meshVolumeM3":0.288,"closedSolid":true,"basis":"Geometría triangulada releída del IFC; envolventes y magnitudes no contractuales."} | {"material":true,"document":true,"quantities":true,"containerGuid":"3ztlotcerHPueDgxP84R6z","containerName":"Planta baja"} | {"id":"architecture","name":"Arquitectura"} | {"profileId":"block_masonry","name":"Fábrica de bloques · acabado mineral claro","materialName":"Bloque hueco de hormigón de árido ligero","physicalMaterialStatus":"known","physicalMaterialSource":"ARQ-OF-20260710 · Arquitectura A101 / p. 3, A103 / p. 5, A106 / p. 8; A301Cuadro de materiales ","appearanceStatus":"criterio_visual","appearanceBasis":"Bloque hueco documentado. Apariencia mineral clara para distinguir el cerramiento; no confirma un revoco ni su espesor.","note":"La apariencia gráfica no modifica ni confirma la especificación física del material."} | {"elementId":"office_0116","ifcGuid":"3epjwF4eXSnx8yGATqhXV2","ifcClass":"IfcWall","buildingId":"office","buildingName":"Edificio de oficinas","sourceDocumentId":"ARQ-OF-20260710","sourceRepresentationKind":"documentary_mesh"} | {"layerId":"architecture","layerName":"Arquitectura","role":"Muro","basis":"Clasificación por función del elemento; no modifica las especificaciones documentales."} | architecture | {"profileId":"block_masonry","name":"Fábrica de bloques · acabado mineral claro","status":"criterio_visual","basis":"Bloque hueco documentado. Apariencia mineral clara para distinguir el cerramiento; no confirma un revoco ni su espesor.","physicalMaterialUnchanged":true} | ARQ-OF-20260710 · Arquitectura A101 / p. 3, A103 / p. 5, A106 / p. 8; A301Cuadro de materiales | Dimensiones contrastadas con los planos; reconstrucción geométrica a partir de documentación de diseño. | 0.2 | Muros segmentados con huecos reales para puertas y ventanas. | Envolvente exterior controlada por la planta de arquitectura; no se han modelado individualmente todas las capas de acabado. | Registro de líneas del PDF general, envolvente de 20 × 10 m; eje local 1 al norte y acceso del lado A al oeste. Estimación de trabajo de implantación de ±0,15 m, pendiente de CAD; no constituye una precisión topográfica garantizada. | Arquitectura | ARQ-OF-20260710 · Arquitectura A101 / p. 3, A103 / p. 5, A106 / p. 8; A301Cuadro de materiales | 285.95 | Arquitectura | Fábrica de bloques · acabado mineral claro | block_masonry | [0.843137,0.823529,0.772549] | 0.96 | 0 | Bloque hueco documentado. Apariencia mineral clara para distinguir el cerramiento; no confirma un revoco ni su espesor. | Arquitectura; BIM · Arquitectura | El plano general de 2026-07-31 mantiene el edificio de oficinas de 200 m², mientras documentación anterior indica su supresión. Se conserva lo dibujado, pendiente de confirmación de la propiedad y del equipo de diseño.
Edificio de oficinas · Fábrica de bloques huecos de hormigón de 200 mm · eje A · tramo 53 | Planos de arquitectura del edificio de oficinas | Bloque hueco de hormigón de árido ligero | 0.9 × 0.2 × 1.1 | 285.95 | 287.05 | 0.198 | office_0117 | yes | 0.32072 | 0.918853 | 1.1 | 2.78 | 0.198 | office | Edificio de oficinas | {"name":"Bloque hueco de hormigón de árido ligero","source":"ARQ-OF-20260710 · Arquitectura A101 / p. 3, A103 / p. 5, A106 / p. 8; A301Cuadro de materiales ","status":"known"} | {"documented":[{"label":"Espesor del muro","value":0.2,"unit":"m","source":"ARQ-OF-20260710 · Arquitectura A101 / p. 3, A103 / p. 5, A106 / p. 8; A301Cuadro de materiales ","status":"documentado"}],"geometry":[{"label":"Dimensiones de la caja local del elemento (X, Y, Z)","value":"0.9 × 0.2 × 1.1","unit":"m","source":"Malla triangulada del elemento en ejes locales del edificio","status":"derivado"},{"label":"Cota mínima absoluta de la malla","value":285.95,"unit":"m","source":"Malla de proyecto y origen altimétrico 285 m","status":"derivado"},{"label":"Cota máxima absoluta de la malla","value":287.05,"unit":"m","source":"Malla de proyecto y origen altimétrico 285 m","status":"derivado"},{"label":"Volumen geométrico bruto","value":0.198,"unit":"m³","source":"Malla cerrada del elemento","status":"derivado"}],"notes":["Las dimensiones documentadas proceden de anotaciones o cuadros; la caja y el volumen se calculan a partir de la malla.","El volumen es exclusivamente geométrico y bruto; no representa una medición neta de material ni una cantidad de compra."]} | {"documentId":"ARQ-OF-20260710","title":"Planos de arquitectura del edificio de oficinas","date":"2026-07-10","sheet":"Arquitectura A101 / p. 3, A103 / p. 5, A106 / p. 8; A301Cuadro de materiales "} | ["El plano general de 2026-07-31 mantiene el edificio de oficinas de 200 m², mientras documentación anterior indica su supresión. Se conserva lo dibujado, pendiente de confirmación de la propiedad y del equipo de diseño.","Envolvente exterior controlada por la planta de arquitectura; no se han modelado individualmente todas las capas de acabado.","Registro de líneas del PDF general, envolvente de 20 × 10 m; eje local 1 al norte y acceso del lado A al oeste. Estimación de trabajo de implantación de ±0,15 m, pendiente de CAD; no constituye una precisión topográfica garantizada."] | {"horizontalStatus":"derivado","verticalStatus":"derivado","baseElevationM":285.95,"note":"Registro de líneas del PDF general, envolvente de 20 × 10 m; eje local 1 al norte y acceso del lado A al oeste. Estimación de trabajo de implantación de ±0,15 m, pendiente de CAD; no constituye una precisión topográfica garantizada."} | {"Pset_WallCommon":{"IsExternal":{"value":true,"source":"ARQ-OF-20260710 · A101, A103 y alzados; elemento de la envolvente exterior identificada en planta","status":"known"}}} | {"boundingBoxM":{"min":[15.016052,74.513458,0.95],"max":[15.336772,75.432311,2.05]},"extentsM":[0.32072,0.918853,1.1],"meshSurfaceM2":2.779999,"meshVolumeM3":0.198,"closedSolid":true,"basis":"Geometría triangulada releída del IFC; envolventes y magnitudes no contractuales."} | {"material":true,"document":true,"quantities":true,"containerGuid":"3ztlotcerHPueDgxP84R6z","containerName":"Planta baja"} | {"id":"architecture","name":"Arquitectura"} | {"profileId":"block_masonry","name":"Fábrica de bloques · acabado mineral claro","materialName":"Bloque hueco de hormigón de árido ligero","physicalMaterialStatus":"known","physicalMaterialSource":"ARQ-OF-20260710 · Arquitectura A101 / p. 3, A103 / p. 5, A106 / p. 8; A301Cuadro de materiales ","appearanceStatus":"criterio_visual","appearanceBasis":"Bloque hueco documentado. Apariencia mineral clara para distinguir el cerramiento; no confirma un revoco ni su espesor.","note":"La apariencia gráfica no modifica ni confirma la especificación física del material."} | {"elementId":"office_0117","ifcGuid":"2Cz23OCVHHIA6rr9A5MlWw","ifcClass":"IfcWall","buildingId":"office","buildingName":"Edificio de oficinas","sourceDocumentId":"ARQ-OF-20260710","sourceRepresentationKind":"documentary_mesh"} | {"layerId":"architecture","layerName":"Arquitectura","role":"Muro","basis":"Clasificación por función del elemento; no modifica las especificaciones documentales."} | architecture | {"profileId":"block_masonry","name":"Fábrica de bloques · acabado mineral claro","status":"criterio_visual","basis":"Bloque hueco documentado. Apariencia mineral clara para distinguir el cerramiento; no confirma un revoco ni su espesor.","physicalMaterialUnchanged":true} | ARQ-OF-20260710 · Arquitectura A101 / p. 3, A103 / p. 5, A106 / p. 8; A301Cuadro de materiales | Dimensiones contrastadas con los planos; reconstrucción geométrica a partir de documentación de diseño. | 0.2 | Muros segmentados con huecos reales para puertas y ventanas. | Envolvente exterior controlada por la planta de arquitectura; no se han modelado individualmente todas las capas de acabado. | Registro de líneas del PDF general, envolvente de 20 × 10 m; eje local 1 al norte y acceso del lado A al oeste. Estimación de trabajo de implantación de ±0,15 m, pendiente de CAD; no constituye una precisión topográfica garantizada. | Arquitectura | ARQ-OF-20260710 · Arquitectura A101 / p. 3, A103 / p. 5, A106 / p. 8; A301Cuadro de materiales | 285.95 | Arquitectura | Fábrica de bloques · acabado mineral claro | block_masonry | [0.843137,0.823529,0.772549] | 0.96 | 0 | Bloque hueco documentado. Apariencia mineral clara para distinguir el cerramiento; no confirma un revoco ni su espesor. | Arquitectura; BIM · Arquitectura | El plano general de 2026-07-31 mantiene el edificio de oficinas de 200 m², mientras documentación anterior indica su supresión. Se conserva lo dibujado, pendiente de confirmación de la propiedad y del equipo de diseño.
Edificio de oficinas · Fábrica de bloques huecos de hormigón de 200 mm · eje A · tramo 54 | Planos de arquitectura del edificio de oficinas | Bloque hueco de hormigón de árido ligero | 0.9 × 0.2 × 1.6 | 289.35 | 290.95 | 0.288 | office_0118 | yes | 0.32072 | 0.918853 | 1.6 | 3.88 | 0.288 | office | Edificio de oficinas | {"name":"Bloque hueco de hormigón de árido ligero","source":"ARQ-OF-20260710 · Arquitectura A101 / p. 3, A103 / p. 5, A106 / p. 8; A301Cuadro de materiales ","status":"known"} | {"documented":[{"label":"Espesor del muro","value":0.2,"unit":"m","source":"ARQ-OF-20260710 · Arquitectura A101 / p. 3, A103 / p. 5, A106 / p. 8; A301Cuadro de materiales ","status":"documentado"}],"geometry":[{"label":"Dimensiones de la caja local del elemento (X, Y, Z)","value":"0.9 × 0.2 × 1.6","unit":"m","source":"Malla triangulada del elemento en ejes locales del edificio","status":"derivado"},{"label":"Cota mínima absoluta de la malla","value":289.35,"unit":"m","source":"Malla de proyecto y origen altimétrico 285 m","status":"derivado"},{"label":"Cota máxima absoluta de la malla","value":290.95,"unit":"m","source":"Malla de proyecto y origen altimétrico 285 m","status":"derivado"},{"label":"Volumen geométrico bruto","value":0.288,"unit":"m³","source":"Malla cerrada del elemento","status":"derivado"}],"notes":["Las dimensiones documentadas proceden de anotaciones o cuadros; la caja y el volumen se calculan a partir de la malla.","El volumen es exclusivamente geométrico y bruto; no representa una medición neta de material ni una cantidad de compra."]} | {"documentId":"ARQ-OF-20260710","title":"Planos de arquitectura del edificio de oficinas","date":"2026-07-10","sheet":"Arquitectura A101 / p. 3, A103 / p. 5, A106 / p. 8; A301Cuadro de materiales "} | ["El plano general de 2026-07-31 mantiene el edificio de oficinas de 200 m², mientras documentación anterior indica su supresión. Se conserva lo dibujado, pendiente de confirmación de la propiedad y del equipo de diseño.","Envolvente exterior controlada por la planta de arquitectura; no se han modelado individualmente todas las capas de acabado.","Registro de líneas del PDF general, envolvente de 20 × 10 m; eje local 1 al norte y acceso del lado A al oeste. Estimación de trabajo de implantación de ±0,15 m, pendiente de CAD; no constituye una precisión topográfica garantizada."] | {"horizontalStatus":"derivado","verticalStatus":"derivado","baseElevationM":285.95,"note":"Registro de líneas del PDF general, envolvente de 20 × 10 m; eje local 1 al norte y acceso del lado A al oeste. Estimación de trabajo de implantación de ±0,15 m, pendiente de CAD; no constituye una precisión topográfica garantizada."} | {"Pset_WallCommon":{"IsExternal":{"value":true,"source":"ARQ-OF-20260710 · A101, A103 y alzados; elemento de la envolvente exterior identificada en planta","status":"known"}}} | {"boundingBoxM":{"min":[15.016052,74.513458,4.35],"max":[15.336772,75.432311,5.95]},"extentsM":[0.32072,0.918853,1.6],"meshSurfaceM2":3.879998,"meshVolumeM3":0.288,"closedSolid":true,"basis":"Geometría triangulada releída del IFC; envolventes y magnitudes no contractuales."} | {"material":true,"document":true,"quantities":true,"containerGuid":"3ztlotcerHPueDgxP84R6z","containerName":"Planta baja"} | {"id":"architecture","name":"Arquitectura"} | {"profileId":"block_masonry","name":"Fábrica de bloques · acabado mineral claro","materialName":"Bloque hueco de hormigón de árido ligero","physicalMaterialStatus":"known","physicalMaterialSource":"ARQ-OF-20260710 · Arquitectura A101 / p. 3, A103 / p. 5, A106 / p. 8; A301Cuadro de materiales ","appearanceStatus":"criterio_visual","appearanceBasis":"Bloque hueco documentado. Apariencia mineral clara para distinguir el cerramiento; no confirma un revoco ni su espesor.","note":"La apariencia gráfica no modifica ni confirma la especificación física del material."} | {"elementId":"office_0118","ifcGuid":"1V74oNF5rIGx2RKWAKbhTW","ifcClass":"IfcWall","buildingId":"office","buildingName":"Edificio de oficinas","sourceDocumentId":"ARQ-OF-20260710","sourceRepresentationKind":"documentary_mesh"} | {"layerId":"architecture","layerName":"Arquitectura","role":"Muro","basis":"Clasificación por función del elemento; no modifica las especificaciones documentales."} | architecture | {"profileId":"block_masonry","name":"Fábrica de bloques · acabado mineral claro","status":"criterio_visual","basis":"Bloque hueco documentado. Apariencia mineral clara para distinguir el cerramiento; no confirma un revoco ni su espesor.","physicalMaterialUnchanged":true} | ARQ-OF-20260710 · Arquitectura A101 / p. 3, A103 / p. 5, A106 / p. 8; A301Cuadro de materiales | Dimensiones contrastadas con los planos; reconstrucción geométrica a partir de documentación de diseño. | 0.2 | Muros segmentados con huecos reales para puertas y ventanas. | Envolvente exterior controlada por la planta de arquitectura; no se han modelado individualmente todas las capas de acabado. | Registro de líneas del PDF general, envolvente de 20 × 10 m; eje local 1 al norte y acceso del lado A al oeste. Estimación de trabajo de implantación de ±0,15 m, pendiente de CAD; no constituye una precisión topográfica garantizada. | Arquitectura | ARQ-OF-20260710 · Arquitectura A101 / p. 3, A103 / p. 5, A106 / p. 8; A301Cuadro de materiales | 285.95 | Arquitectura | Fábrica de bloques · acabado mineral claro | block_masonry | [0.843137,0.823529,0.772549] | 0.96 | 0 | Bloque hueco documentado. Apariencia mineral clara para distinguir el cerramiento; no confirma un revoco ni su espesor. | Arquitectura; BIM · Arquitectura | El plano general de 2026-07-31 mantiene el edificio de oficinas de 200 m², mientras documentación anterior indica su supresión. Se conserva lo dibujado, pendiente de confirmación de la propiedad y del equipo de diseño.
Edificio de oficinas · Fábrica de bloques huecos de hormigón de 200 mm · eje A · tramo 55 | Planos de arquitectura del edificio de oficinas | Bloque hueco de hormigón de árido ligero | 1.45 × 0.2 × 1.1 | 285.95 | 287.05 | 0.319 | office_0119 | yes | 0.395631 | 1.46373 | 1.1 | 4.21 | 0.319 | office | Edificio de oficinas | {"name":"Bloque hueco de hormigón de árido ligero","source":"ARQ-OF-20260710 · Arquitectura A101 / p. 3, A103 / p. 5, A106 / p. 8; A301Cuadro de materiales ","status":"known"} | {"documented":[{"label":"Espesor del muro","value":0.2,"unit":"m","source":"ARQ-OF-20260710 · Arquitectura A101 / p. 3, A103 / p. 5, A106 / p. 8; A301Cuadro de materiales ","status":"documentado"}],"geometry":[{"label":"Dimensiones de la caja local del elemento (X, Y, Z)","value":"1.45 × 0.2 × 1.1","unit":"m","source":"Malla triangulada del elemento en ejes locales del edificio","status":"derivado"},{"label":"Cota mínima absoluta de la malla","value":285.95,"unit":"m","source":"Malla de proyecto y origen altimétrico 285 m","status":"derivado"},{"label":"Cota máxima absoluta de la malla","value":287.05,"unit":"m","source":"Malla de proyecto y origen altimétrico 285 m","status":"derivado"},{"label":"Volumen geométrico bruto","value":0.319,"unit":"m³","source":"Malla cerrada del elemento","status":"derivado"}],"notes":["Las dimensiones documentadas proceden de anotaciones o cuadros; la caja y el volumen se calculan a partir de la malla.","El volumen es exclusivamente geométrico y bruto; no representa una medición neta de material ni una cantidad de compra."]} | {"documentId":"ARQ-OF-20260710","title":"Planos de arquitectura del edificio de oficinas","date":"2026-07-10","sheet":"Arquitectura A101 / p. 3, A103 / p. 5, A106 / p. 8; A301Cuadro de materiales "} | ["El plano general de 2026-07-31 mantiene el edificio de oficinas de 200 m², mientras documentación anterior indica su supresión. Se conserva lo dibujado, pendiente de confirmación de la propiedad y del equipo de diseño.","Envolvente exterior controlada por la planta de arquitectura; no se han modelado individualmente todas las capas de acabado.","Registro de líneas del PDF general, envolvente de 20 × 10 m; eje local 1 al norte y acceso del lado A al oeste. Estimación de trabajo de implantación de ±0,15 m, pendiente de CAD; no constituye una precisión topográfica garantizada."] | {"horizontalStatus":"derivado","verticalStatus":"derivado","baseElevationM":285.95,"note":"Registro de líneas del PDF general, envolvente de 20 × 10 m; eje local 1 al norte y acceso del lado A al oeste. Estimación de trabajo de implantación de ±0,15 m, pendiente de CAD; no constituye una precisión topográfica garantizada."} | {"Pset_WallCommon":{"IsExternal":{"value":true,"source":"ARQ-OF-20260710 · A101, A103 y alzados; elemento de la envolvente exterior identificada en planta","status":"known"}}} | {"boundingBoxM":{"min":[14.818557,73.076971,0.95],"max":[15.214188,74.540699,2.05]},"extentsM":[0.395631,1.463728,1.1],"meshSurfaceM2":4.21,"meshVolumeM3":0.319,"closedSolid":true,"basis":"Geometría triangulada releída del IFC; envolventes y magnitudes no contractuales."} | {"material":true,"document":true,"quantities":true,"containerGuid":"3ztlotcerHPueDgxP84R6z","containerName":"Planta baja"} | {"id":"architecture","name":"Arquitectura"} | {"profileId":"block_masonry","name":"Fábrica de bloques · acabado mineral claro","materialName":"Bloque hueco de hormigón de árido ligero","physicalMaterialStatus":"known","physicalMaterialSource":"ARQ-OF-20260710 · Arquitectura A101 / p. 3, A103 / p. 5, A106 / p. 8; A301Cuadro de materiales ","appearanceStatus":"criterio_visual","appearanceBasis":"Bloque hueco documentado. Apariencia mineral clara para distinguir el cerramiento; no confirma un revoco ni su espesor.","note":"La apariencia gráfica no modifica ni confirma la especificación física del material."} | {"elementId":"office_0119","ifcGuid":"1FR1vrz99NGQiexMw2duDP","ifcClass":"IfcWall","buildingId":"office","buildingName":"Edificio de oficinas","sourceDocumentId":"ARQ-OF-20260710","sourceRepresentationKind":"documentary_mesh"} | {"layerId":"architecture","layerName":"Arquitectura","role":"Muro","basis":"Clasificación por función del elemento; no modifica las especificaciones documentales."} | architecture | {"profileId":"block_masonry","name":"Fábrica de bloques · acabado mineral claro","status":"criterio_visual","basis":"Bloque hueco documentado. Apariencia mineral clara para distinguir el cerramiento; no confirma un revoco ni su espesor.","physicalMaterialUnchanged":true} | ARQ-OF-20260710 · Arquitectura A101 / p. 3, A103 / p. 5, A106 / p. 8; A301Cuadro de materiales | Dimensiones contrastadas con los planos; reconstrucción geométrica a partir de documentación de diseño. | 0.2 | Muros segmentados con huecos reales para puertas y ventanas. | Envolvente exterior controlada por la planta de arquitectura; no se han modelado individualmente todas las capas de acabado. | Registro de líneas del PDF general, envolvente de 20 × 10 m; eje local 1 al norte y acceso del lado A al oeste. Estimación de trabajo de implantación de ±0,15 m, pendiente de CAD; no constituye una precisión topográfica garantizada. | Arquitectura | ARQ-OF-20260710 · Arquitectura A101 / p. 3, A103 / p. 5, A106 / p. 8; A301Cuadro de materiales | 285.95 | Arquitectura | Fábrica de bloques · acabado mineral claro | block_masonry | [0.843137,0.823529,0.772549] | 0.96 | 0 | Bloque hueco documentado. Apariencia mineral clara para distinguir el cerramiento; no confirma un revoco ni su espesor. | Arquitectura; BIM · Arquitectura | El plano general de 2026-07-31 mantiene el edificio de oficinas de 200 m², mientras documentación anterior indica su supresión. Se conserva lo dibujado, pendiente de confirmación de la propiedad y del equipo de diseño.
Edificio de oficinas · Fábrica de bloques huecos de hormigón de 200 mm · eje A · tramo 56 | Planos de arquitectura del edificio de oficinas | Bloque hueco de hormigón de árido ligero | 1.45 × 0.2 × 1.2 | 287.05 | 288.25 | 0.348 | office_0120 | yes | 0.395631 | 1.46373 | 1.2 | 4.54 | 0.348 | office | Edificio de oficinas | {"name":"Bloque hueco de hormigón de árido ligero","source":"ARQ-OF-20260710 · Arquitectura A101 / p. 3, A103 / p. 5, A106 / p. 8; A301Cuadro de materiales ","status":"known"} | {"documented":[{"label":"Espesor del muro","value":0.2,"unit":"m","source":"ARQ-OF-20260710 · Arquitectura A101 / p. 3, A103 / p. 5, A106 / p. 8; A301Cuadro de materiales ","status":"documentado"}],"geometry":[{"label":"Dimensiones de la caja local del elemento (X, Y, Z)","value":"1.45 × 0.2 × 1.2","unit":"m","source":"Malla triangulada del elemento en ejes locales del edificio","status":"derivado"},{"label":"Cota mínima absoluta de la malla","value":287.05,"unit":"m","source":"Malla de proyecto y origen altimétrico 285 m","status":"derivado"},{"label":"Cota máxima absoluta de la malla","value":288.25,"unit":"m","source":"Malla de proyecto y origen altimétrico 285 m","status":"derivado"},{"label":"Volumen geométrico bruto","value":0.348,"unit":"m³","source":"Malla cerrada del elemento","status":"derivado"}],"notes":["Las dimensiones documentadas proceden de anotaciones o cuadros; la caja y el volumen se calculan a partir de la malla.","El volumen es exclusivamente geométrico y bruto; no representa una medición neta de material ni una cantidad de compra."]} | {"documentId":"ARQ-OF-20260710","title":"Planos de arquitectura del edificio de oficinas","date":"2026-07-10","sheet":"Arquitectura A101 / p. 3, A103 / p. 5, A106 / p. 8; A301Cuadro de materiales "} | ["El plano general de 2026-07-31 mantiene el edificio de oficinas de 200 m², mientras documentación anterior indica su supresión. Se conserva lo dibujado, pendiente de confirmación de la propiedad y del equipo de diseño.","Envolvente exterior controlada por la planta de arquitectura; no se han modelado individualmente todas las capas de acabado.","Registro de líneas del PDF general, envolvente de 20 × 10 m; eje local 1 al norte y acceso del lado A al oeste. Estimación de trabajo de implantación de ±0,15 m, pendiente de CAD; no constituye una precisión topográfica garantizada."] | {"horizontalStatus":"derivado","verticalStatus":"derivado","baseElevationM":285.95,"note":"Registro de líneas del PDF general, envolvente de 20 × 10 m; eje local 1 al norte y acceso del lado A al oeste. Estimación de trabajo de implantación de ±0,15 m, pendiente de CAD; no constituye una precisión topográfica garantizada."} | {"Pset_WallCommon":{"IsExternal":{"value":true,"source":"ARQ-OF-20260710 · A101, A103 y alzados; elemento de la envolvente exterior identificada en planta","status":"known"}}} | {"boundingBoxM":{"min":[14.818557,73.076971,2.05],"max":[15.214188,74.540699,3.25]},"extentsM":[0.395631,1.463728,1.2],"meshSurfaceM2":4.54,"meshVolumeM3":0.348,"closedSolid":true,"basis":"Geometría triangulada releída del IFC; envolventes y magnitudes no contractuales."} | {"material":true,"document":true,"quantities":true,"containerGuid":"3ztlotcerHPueDgxP84R6z","containerName":"Planta baja"} | {"id":"architecture","name":"Arquitectura"} | {"profileId":"block_masonry","name":"Fábrica de bloques · acabado mineral claro","materialName":"Bloque hueco de hormigón de árido ligero","physicalMaterialStatus":"known","physicalMaterialSource":"ARQ-OF-20260710 · Arquitectura A101 / p. 3, A103 / p. 5, A106 / p. 8; A301Cuadro de materiales ","appearanceStatus":"criterio_visual","appearanceBasis":"Bloque hueco documentado. Apariencia mineral clara para distinguir el cerramiento; no confirma un revoco ni su espesor.","note":"La apariencia gráfica no modifica ni confirma la especificación física del material."} | {"elementId":"office_0120","ifcGuid":"0hXtffhfHTcebgMSWIYggX","ifcClass":"IfcWall","buildingId":"office","buildingName":"Edificio de oficinas","sourceDocumentId":"ARQ-OF-20260710","sourceRepresentationKind":"documentary_mesh"} | {"layerId":"architecture","layerName":"Arquitectura","role":"Muro","basis":"Clasificación por función del elemento; no modifica las especificaciones documentales."} | architecture | {"profileId":"block_masonry","name":"Fábrica de bloques · acabado mineral claro","status":"criterio_visual","basis":"Bloque hueco documentado. Apariencia mineral clara para distinguir el cerramiento; no confirma un revoco ni su espesor.","physicalMaterialUnchanged":true} | ARQ-OF-20260710 · Arquitectura A101 / p. 3, A103 / p. 5, A106 / p. 8; A301Cuadro de materiales | Dimensiones contrastadas con los planos; reconstrucción geométrica a partir de documentación de diseño. | 0.2 | Muros segmentados con huecos reales para puertas y ventanas. | Envolvente exterior controlada por la planta de arquitectura; no se han modelado individualmente todas las capas de acabado. | Registro de líneas del PDF general, envolvente de 20 × 10 m; eje local 1 al norte y acceso del lado A al oeste. Estimación de trabajo de implantación de ±0,15 m, pendiente de CAD; no constituye una precisión topográfica garantizada. | Arquitectura | ARQ-OF-20260710 · Arquitectura A101 / p. 3, A103 / p. 5, A106 / p. 8; A301Cuadro de materiales | 285.95 | Arquitectura | Fábrica de bloques · acabado mineral claro | block_masonry | [0.843137,0.823529,0.772549] | 0.96 | 0 | Bloque hueco documentado. Apariencia mineral clara para distinguir el cerramiento; no confirma un revoco ni su espesor. | Arquitectura; BIM · Arquitectura | El plano general de 2026-07-31 mantiene el edificio de oficinas de 200 m², mientras documentación anterior indica su supresión. Se conserva lo dibujado, pendiente de confirmación de la propiedad y del equipo de diseño.
Edificio de oficinas · Fábrica de bloques huecos de hormigón de 200 mm · eje A · tramo 57 | Planos de arquitectura del edificio de oficinas | Bloque hueco de hormigón de árido ligero | 1.45 × 0.2 × 1.1 | 288.25 | 289.35 | 0.319 | office_0121 | yes | 0.395631 | 1.46373 | 1.1 | 4.21 | 0.319 | office | Edificio de oficinas | {"name":"Bloque hueco de hormigón de árido ligero","source":"ARQ-OF-20260710 · Arquitectura A101 / p. 3, A103 / p. 5, A106 / p. 8; A301Cuadro de materiales ","status":"known"} | {"documented":[{"label":"Espesor del muro","value":0.2,"unit":"m","source":"ARQ-OF-20260710 · Arquitectura A101 / p. 3, A103 / p. 5, A106 / p. 8; A301Cuadro de materiales ","status":"documentado"}],"geometry":[{"label":"Dimensiones de la caja local del elemento (X, Y, Z)","value":"1.45 × 0.2 × 1.1","unit":"m","source":"Malla triangulada del elemento en ejes locales del edificio","status":"derivado"},{"label":"Cota mínima absoluta de la malla","value":288.25,"unit":"m","source":"Malla de proyecto y origen altimétrico 285 m","status":"derivado"},{"label":"Cota máxima absoluta de la malla","value":289.35,"unit":"m","source":"Malla de proyecto y origen altimétrico 285 m","status":"derivado"},{"label":"Volumen geométrico bruto","value":0.319,"unit":"m³","source":"Malla cerrada del elemento","status":"derivado"}],"notes":["Las dimensiones documentadas proceden de anotaciones o cuadros; la caja y el volumen se calculan a partir de la malla.","El volumen es exclusivamente geométrico y bruto; no representa una medición neta de material ni una cantidad de compra."]} | {"documentId":"ARQ-OF-20260710","title":"Planos de arquitectura del edificio de oficinas","date":"2026-07-10","sheet":"Arquitectura A101 / p. 3, A103 / p. 5, A106 / p. 8; A301Cuadro de materiales "} | ["El plano general de 2026-07-31 mantiene el edificio de oficinas de 200 m², mientras documentación anterior indica su supresión. Se conserva lo dibujado, pendiente de confirmación de la propiedad y del equipo de diseño.","Envolvente exterior controlada por la planta de arquitectura; no se han modelado individualmente todas las capas de acabado.","Registro de líneas del PDF general, envolvente de 20 × 10 m; eje local 1 al norte y acceso del lado A al oeste. Estimación de trabajo de implantación de ±0,15 m, pendiente de CAD; no constituye una precisión topográfica garantizada."] | {"horizontalStatus":"derivado","verticalStatus":"derivado","baseElevationM":285.95,"note":"Registro de líneas del PDF general, envolvente de 20 × 10 m; eje local 1 al norte y acceso del lado A al oeste. Estimación de trabajo de implantación de ±0,15 m, pendiente de CAD; no constituye una precisión topográfica garantizada."} | {"Pset_WallCommon":{"IsExternal":{"value":true,"source":"ARQ-OF-20260710 · A101, A103 y alzados; elemento de la envolvente exterior identificada en planta","status":"known"}}} | {"boundingBoxM":{"min":[14.818557,73.076971,3.25],"max":[15.214188,74.540699,4.35]},"extentsM":[0.395631,1.463728,1.1],"meshSurfaceM2":4.21,"meshVolumeM3":0.319,"closedSolid":true,"basis":"Geometría triangulada releída del IFC; envolventes y magnitudes no contractuales."} | {"material":true,"document":true,"quantities":true,"containerGuid":"3ztlotcerHPueDgxP84R6z","containerName":"Planta baja"} | {"id":"architecture","name":"Arquitectura"} | {"profileId":"block_masonry","name":"Fábrica de bloques · acabado mineral claro","materialName":"Bloque hueco de hormigón de árido ligero","physicalMaterialStatus":"known","physicalMaterialSource":"ARQ-OF-20260710 · Arquitectura A101 / p. 3, A103 / p. 5, A106 / p. 8; A301Cuadro de materiales ","appearanceStatus":"criterio_visual","appearanceBasis":"Bloque hueco documentado. Apariencia mineral clara para distinguir el cerramiento; no confirma un revoco ni su espesor.","note":"La apariencia gráfica no modifica ni confirma la especificación física del material."} | {"elementId":"office_0121","ifcGuid":"2Xf7tYowTLCAIAe9uF6wo5","ifcClass":"IfcWall","buildingId":"office","buildingName":"Edificio de oficinas","sourceDocumentId":"ARQ-OF-20260710","sourceRepresentationKind":"documentary_mesh"} | {"layerId":"architecture","layerName":"Arquitectura","role":"Muro","basis":"Clasificación por función del elemento; no modifica las especificaciones documentales."} | architecture | {"profileId":"block_masonry","name":"Fábrica de bloques · acabado mineral claro","status":"criterio_visual","basis":"Bloque hueco documentado. Apariencia mineral clara para distinguir el cerramiento; no confirma un revoco ni su espesor.","physicalMaterialUnchanged":true} | ARQ-OF-20260710 · Arquitectura A101 / p. 3, A103 / p. 5, A106 / p. 8; A301Cuadro de materiales | Dimensiones contrastadas con los planos; reconstrucción geométrica a partir de documentación de diseño. | 0.2 | Muros segmentados con huecos reales para puertas y ventanas. | Envolvente exterior controlada por la planta de arquitectura; no se han modelado individualmente todas las capas de acabado. | Registro de líneas del PDF general, envolvente de 20 × 10 m; eje local 1 al norte y acceso del lado A al oeste. Estimación de trabajo de implantación de ±0,15 m, pendiente de CAD; no constituye una precisión topográfica garantizada. | Arquitectura | ARQ-OF-20260710 · Arquitectura A101 / p. 3, A103 / p. 5, A106 / p. 8; A301Cuadro de materiales | 285.95 | Arquitectura | Fábrica de bloques · acabado mineral claro | block_masonry | [0.843137,0.823529,0.772549] | 0.96 | 0 | Bloque hueco documentado. Apariencia mineral clara para distinguir el cerramiento; no confirma un revoco ni su espesor. | Arquitectura; BIM · Arquitectura | El plano general de 2026-07-31 mantiene el edificio de oficinas de 200 m², mientras documentación anterior indica su supresión. Se conserva lo dibujado, pendiente de confirmación de la propiedad y del equipo de diseño.
Edificio de oficinas · Fábrica de bloques huecos de hormigón de 200 mm · eje A · tramo 58 | Planos de arquitectura del edificio de oficinas | Bloque hueco de hormigón de árido ligero | 1.45 × 0.2 × 1.6 | 289.35 | 290.95 | 0.464 | office_0122 | yes | 0.395631 | 1.46373 | 1.6 | 5.86 | 0.464 | office | Edificio de oficinas | {"name":"Bloque hueco de hormigón de árido ligero","source":"ARQ-OF-20260710 · Arquitectura A101 / p. 3, A103 / p. 5, A106 / p. 8; A301Cuadro de materiales ","status":"known"} | {"documented":[{"label":"Espesor del muro","value":0.2,"unit":"m","source":"ARQ-OF-20260710 · Arquitectura A101 / p. 3, A103 / p. 5, A106 / p. 8; A301Cuadro de materiales ","status":"documentado"}],"geometry":[{"label":"Dimensiones de la caja local del elemento (X, Y, Z)","value":"1.45 × 0.2 × 1.6","unit":"m","source":"Malla triangulada del elemento en ejes locales del edificio","status":"derivado"},{"label":"Cota mínima absoluta de la malla","value":289.35,"unit":"m","source":"Malla de proyecto y origen altimétrico 285 m","status":"derivado"},{"label":"Cota máxima absoluta de la malla","value":290.95,"unit":"m","source":"Malla de proyecto y origen altimétrico 285 m","status":"derivado"},{"label":"Volumen geométrico bruto","value":0.464,"unit":"m³","source":"Malla cerrada del elemento","status":"derivado"}],"notes":["Las dimensiones documentadas proceden de anotaciones o cuadros; la caja y el volumen se calculan a partir de la malla.","El volumen es exclusivamente geométrico y bruto; no representa una medición neta de material ni una cantidad de compra."]} | {"documentId":"ARQ-OF-20260710","title":"Planos de arquitectura del edificio de oficinas","date":"2026-07-10","sheet":"Arquitectura A101 / p. 3, A103 / p. 5, A106 / p. 8; A301Cuadro de materiales "} | ["El plano general de 2026-07-31 mantiene el edificio de oficinas de 200 m², mientras documentación anterior indica su supresión. Se conserva lo dibujado, pendiente de confirmación de la propiedad y del equipo de diseño.","Envolvente exterior controlada por la planta de arquitectura; no se han modelado individualmente todas las capas de acabado.","Registro de líneas del PDF general, envolvente de 20 × 10 m; eje local 1 al norte y acceso del lado A al oeste. Estimación de trabajo de implantación de ±0,15 m, pendiente de CAD; no constituye una precisión topográfica garantizada."] | {"horizontalStatus":"derivado","verticalStatus":"derivado","baseElevationM":285.95,"note":"Registro de líneas del PDF general, envolvente de 20 × 10 m; eje local 1 al norte y acceso del lado A al oeste. Estimación de trabajo de implantación de ±0,15 m, pendiente de CAD; no constituye una precisión topográfica garantizada."} | {"Pset_WallCommon":{"IsExternal":{"value":true,"source":"ARQ-OF-20260710 · A101, A103 y alzados; elemento de la envolvente exterior identificada en planta","status":"known"}}} | {"boundingBoxM":{"min":[14.818557,73.076971,4.35],"max":[15.214188,74.540699,5.95]},"extentsM":[0.395631,1.463728,1.6],"meshSurfaceM2":5.86,"meshVolumeM3":0.464,"closedSolid":true,"basis":"Geometría triangulada releída del IFC; envolventes y magnitudes no contractuales."} | {"material":true,"document":true,"quantities":true,"containerGuid":"3ztlotcerHPueDgxP84R6z","containerName":"Planta baja"} | {"id":"architecture","name":"Arquitectura"} | {"profileId":"block_masonry","name":"Fábrica de bloques · acabado mineral claro","materialName":"Bloque hueco de hormigón de árido ligero","physicalMaterialStatus":"known","physicalMaterialSource":"ARQ-OF-20260710 · Arquitectura A101 / p. 3, A103 / p. 5, A106 / p. 8; A301Cuadro de materiales ","appearanceStatus":"criterio_visual","appearanceBasis":"Bloque hueco documentado. Apariencia mineral clara para distinguir el cerramiento; no confirma un revoco ni su espesor.","note":"La apariencia gráfica no modifica ni confirma la especificación física del material."} | {"elementId":"office_0122","ifcGuid":"2RthGuZHvG7A93Z1LqFSEU","ifcClass":"IfcWall","buildingId":"office","buildingName":"Edificio de oficinas","sourceDocumentId":"ARQ-OF-20260710","sourceRepresentationKind":"documentary_mesh"} | {"layerId":"architecture","layerName":"Arquitectura","role":"Muro","basis":"Clasificación por función del elemento; no modifica las especificaciones documentales."} | architecture | {"profileId":"block_masonry","name":"Fábrica de bloques · acabado mineral claro","status":"criterio_visual","basis":"Bloque hueco documentado. Apariencia mineral clara para distinguir el cerramiento; no confirma un revoco ni su espesor.","physicalMaterialUnchanged":true} | ARQ-OF-20260710 · Arquitectura A101 / p. 3, A103 / p. 5, A106 / p. 8; A301Cuadro de materiales | Dimensiones contrastadas con los planos; reconstrucción geométrica a partir de documentación de diseño. | 0.2 | Muros segmentados con huecos reales para puertas y ventanas. | Envolvente exterior controlada por la planta de arquitectura; no se han modelado individualmente todas las capas de acabado. | Registro de líneas del PDF general, envolvente de 20 × 10 m; eje local 1 al norte y acceso del lado A al oeste. Estimación de trabajo de implantación de ±0,15 m, pendiente de CAD; no constituye una precisión topográfica garantizada. | Arquitectura | ARQ-OF-20260710 · Arquitectura A101 / p. 3, A103 / p. 5, A106 / p. 8; A301Cuadro de materiales | 285.95 | Arquitectura | Fábrica de bloques · acabado mineral claro | block_masonry | [0.843137,0.823529,0.772549] | 0.96 | 0 | Bloque hueco documentado. Apariencia mineral clara para distinguir el cerramiento; no confirma un revoco ni su espesor. | Arquitectura; BIM · Arquitectura | El plano general de 2026-07-31 mantiene el edificio de oficinas de 200 m², mientras documentación anterior indica su supresión. Se conserva lo dibujado, pendiente de confirmación de la propiedad y del equipo de diseño.
Edificio de oficinas · Fábrica de bloques huecos de hormigón de 200 mm · eje B · tramo 01 | Planos de arquitectura del edificio de oficinas | Bloque hueco de hormigón de árido ligero | 0.7 × 0.2 × 1.1 | 285.95 | 287.05 | 0.154 | office_0123 | yes | 0.293479 | 0.720717 | 1.1 | 2.26 | 0.154 | office | Edificio de oficinas | {"name":"Bloque hueco de hormigón de árido ligero","source":"ARQ-OF-20260710 · Arquitectura A101 / p. 3, A103 / p. 5, A106 / p. 8; A301Cuadro de materiales ","status":"known"} | {"documented":[{"label":"Espesor del muro","value":0.2,"unit":"m","source":"ARQ-OF-20260710 · Arquitectura A101 / p. 3, A103 / p. 5, A106 / p. 8; A301Cuadro de materiales ","status":"documentado"}],"geometry":[{"label":"Dimensiones de la caja local del elemento (X, Y, Z)","value":"0.7 × 0.2 × 1.1","unit":"m","source":"Malla triangulada del elemento en ejes locales del edificio","status":"derivado"},{"label":"Cota mínima absoluta de la malla","value":285.95,"unit":"m","source":"Malla de proyecto y origen altimétrico 285 m","status":"derivado"},{"label":"Cota máxima absoluta de la malla","value":287.05,"unit":"m","source":"Malla de proyecto y origen altimétrico 285 m","status":"derivado"},{"label":"Volumen geométrico bruto","value":0.154,"unit":"m³","source":"Malla cerrada del elemento","status":"derivado"}],"notes":["Las dimensiones documentadas proceden de anotaciones o cuadros; la caja y el volumen se calculan a partir de la malla.","El volumen es exclusivamente geométrico y bruto; no representa una medición neta de material ni una cantidad de compra."]} | {"documentId":"ARQ-OF-20260710","title":"Planos de arquitectura del edificio de oficinas","date":"2026-07-10","sheet":"Arquitectura A101 / p. 3, A103 / p. 5, A106 / p. 8; A301Cuadro de materiales "} | ["El plano general de 2026-07-31 mantiene el edificio de oficinas de 200 m², mientras documentación anterior indica su supresión. Se conserva lo dibujado, pendiente de confirmación de la propiedad y del equipo de diseño.","Envolvente exterior controlada por la planta de arquitectura; no se han modelado individualmente todas las capas de acabado.","Registro de líneas del PDF general, envolvente de 20 × 10 m; eje local 1 al norte y acceso del lado A al oeste. Estimación de trabajo de implantación de ±0,15 m, pendiente de CAD; no constituye una precisión topográfica garantizada."] | {"horizontalStatus":"derivado","verticalStatus":"derivado","baseElevationM":285.95,"note":"Registro de líneas del PDF general, envolvente de 20 × 10 m; eje local 1 al norte y acceso del lado A al oeste. Estimación de trabajo de implantación de ±0,15 m, pendiente de CAD; no constituye una precisión topográfica garantizada."} | {"Pset_WallCommon":{"IsExternal":{"value":true,"source":"ARQ-OF-20260710 · A101, A103 y alzados; elemento de la envolvente exterior identificada en planta","status":"known"}}} | {"boundingBoxM":{"min":[27.155964,90.862312,0.95],"max":[27.449443,91.583029,2.05]},"extentsM":[0.293479,0.720717,1.1],"meshSurfaceM2":2.260001,"meshVolumeM3":0.154,"closedSolid":true,"basis":"Geometría triangulada releída del IFC; envolventes y magnitudes no contractuales."} | {"material":true,"document":true,"quantities":true,"containerGuid":"3ztlotcerHPueDgxP84R6z","containerName":"Planta baja"} | {"id":"architecture","name":"Arquitectura"} | {"profileId":"block_masonry","name":"Fábrica de bloques · acabado mineral claro","materialName":"Bloque hueco de hormigón de árido ligero","physicalMaterialStatus":"known","physicalMaterialSource":"ARQ-OF-20260710 · Arquitectura A101 / p. 3, A103 / p. 5, A106 / p. 8; A301Cuadro de materiales ","appearanceStatus":"criterio_visual","appearanceBasis":"Bloque hueco documentado. Apariencia mineral clara para distinguir el cerramiento; no confirma un revoco ni su espesor.","note":"La apariencia gráfica no modifica ni confirma la especificación física del material."} | {"elementId":"office_0123","ifcGuid":"1z7$O7TD1OhgQkZ$LVmARq","ifcClass":"IfcWall","buildingId":"office","buildingName":"Edificio de oficinas","sourceDocumentId":"ARQ-OF-20260710","sourceRepresentationKind":"documentary_mesh"} | {"layerId":"architecture","layerName":"Arquitectura","role":"Muro","basis":"Clasificación por función del elemento; no modifica las especificaciones documentales."} | architecture | {"profileId":"block_masonry","name":"Fábrica de bloques · acabado mineral claro","status":"criterio_visual","basis":"Bloque hueco documentado. Apariencia mineral clara para distinguir el cerramiento; no confirma un revoco ni su espesor.","physicalMaterialUnchanged":true} | ARQ-OF-20260710 · Arquitectura A101 / p. 3, A103 / p. 5, A106 / p. 8; A301Cuadro de materiales | Dimensiones contrastadas con los planos; reconstrucción geométrica a partir de documentación de diseño. | 0.2 | Muros segmentados con huecos reales para puertas y ventanas. | Envolvente exterior controlada por la planta de arquitectura; no se han modelado individualmente todas las capas de acabado. | Registro de líneas del PDF general, envolvente de 20 × 10 m; eje local 1 al norte y acceso del lado A al oeste. Estimación de trabajo de implantación de ±0,15 m, pendiente de CAD; no constituye una precisión topográfica garantizada. | Arquitectura | ARQ-OF-20260710 · Arquitectura A101 / p. 3, A103 / p. 5, A106 / p. 8; A301Cuadro de materiales | 285.95 | Arquitectura | Fábrica de bloques · acabado mineral claro | block_masonry | [0.843137,0.823529,0.772549] | 0.96 | 0 | Bloque hueco documentado. Apariencia mineral clara para distinguir el cerramiento; no confirma un revoco ni su espesor. | Arquitectura; BIM · Arquitectura | El plano general de 2026-07-31 mantiene el edificio de oficinas de 200 m², mientras documentación anterior indica su supresión. Se conserva lo dibujado, pendiente de confirmación de la propiedad y del equipo de diseño.
Edificio de oficinas · Fábrica de bloques huecos de hormigón de 200 mm · eje B · tramo 02 | Planos de arquitectura del edificio de oficinas | Bloque hueco de hormigón de árido ligero | 0.7 × 0.2 × 1.2 | 287.05 | 288.25 | 0.168 | office_0124 | yes | 0.293479 | 0.720717 | 1.2 | 2.44 | 0.168 | office | Edificio de oficinas | {"name":"Bloque hueco de hormigón de árido ligero","source":"ARQ-OF-20260710 · Arquitectura A101 / p. 3, A103 / p. 5, A106 / p. 8; A301Cuadro de materiales ","status":"known"} | {"documented":[{"label":"Espesor del muro","value":0.2,"unit":"m","source":"ARQ-OF-20260710 · Arquitectura A101 / p. 3, A103 / p. 5, A106 / p. 8; A301Cuadro de materiales ","status":"documentado"}],"geometry":[{"label":"Dimensiones de la caja local del elemento (X, Y, Z)","value":"0.7 × 0.2 × 1.2","unit":"m","source":"Malla triangulada del elemento en ejes locales del edificio","status":"derivado"},{"label":"Cota mínima absoluta de la malla","value":287.05,"unit":"m","source":"Malla de proyecto y origen altimétrico 285 m","status":"derivado"},{"label":"Cota máxima absoluta de la malla","value":288.25,"unit":"m","source":"Malla de proyecto y origen altimétrico 285 m","status":"derivado"},{"label":"Volumen geométrico bruto","value":0.168,"unit":"m³","source":"Malla cerrada del elemento","status":"derivado"}],"notes":["Las dimensiones documentadas proceden de anotaciones o cuadros; la caja y el volumen se calculan a partir de la malla.","El volumen es exclusivamente geométrico y bruto; no representa una medición neta de material ni una cantidad de compra."]} | {"documentId":"ARQ-OF-20260710","title":"Planos de arquitectura del edificio de oficinas","date":"2026-07-10","sheet":"Arquitectura A101 / p. 3, A103 / p. 5, A106 / p. 8; A301Cuadro de materiales "} | ["El plano general de 2026-07-31 mantiene el edificio de oficinas de 200 m², mientras documentación anterior indica su supresión. Se conserva lo dibujado, pendiente de confirmación de la propiedad y del equipo de diseño.","Envolvente exterior controlada por la planta de arquitectura; no se han modelado individualmente todas las capas de acabado.","Registro de líneas del PDF general, envolvente de 20 × 10 m; eje local 1 al norte y acceso del lado A al oeste. Estimación de trabajo de implantación de ±0,15 m, pendiente de CAD; no constituye una precisión topográfica garantizada."] | {"horizontalStatus":"derivado","verticalStatus":"derivado","baseElevationM":285.95,"note":"Registro de líneas del PDF general, envolvente de 20 × 10 m; eje local 1 al norte y acceso del lado A al oeste. Estimación de trabajo de implantación de ±0,15 m, pendiente de CAD; no constituye una precisión topográfica garantizada."} | {"Pset_WallCommon":{"IsExternal":{"value":true,"source":"ARQ-OF-20260710 · A101, A103 y alzados; elemento de la envolvente exterior identificada en planta","status":"known"}}} | {"boundingBoxM":{"min":[27.155964,90.862312,2.05],"max":[27.449443,91.583029,3.25]},"extentsM":[0.293479,0.720717,1.2],"meshSurfaceM2":2.440001,"meshVolumeM3":0.168,"closedSolid":true,"basis":"Geometría triangulada releída del IFC; envolventes y magnitudes no contractuales."} | {"material":true,"document":true,"quantities":true,"containerGuid":"3ztlotcerHPueDgxP84R6z","containerName":"Planta baja"} | {"id":"architecture","name":"Arquitectura"} | {"profileId":"block_masonry","name":"Fábrica de bloques · acabado mineral claro","materialName":"Bloque hueco de hormigón de árido ligero","physicalMaterialStatus":"known","physicalMaterialSource":"ARQ-OF-20260710 · Arquitectura A101 / p. 3, A103 / p. 5, A106 / p. 8; A301Cuadro de materiales ","appearanceStatus":"criterio_visual","appearanceBasis":"Bloque hueco documentado. Apariencia mineral clara para distinguir el cerramiento; no confirma un revoco ni su espesor.","note":"La apariencia gráfica no modifica ni confirma la especificación física del material."} | {"elementId":"office_0124","ifcGuid":"2OyXy$RqPIL9mPkkFM3t_p","ifcClass":"IfcWall","buildingId":"office","buildingName":"Edificio de oficinas","sourceDocumentId":"ARQ-OF-20260710","sourceRepresentationKind":"documentary_mesh"} | {"layerId":"architecture","layerName":"Arquitectura","role":"Muro","basis":"Clasificación por función del elemento; no modifica las especificaciones documentales."} | architecture | {"profileId":"block_masonry","name":"Fábrica de bloques · acabado mineral claro","status":"criterio_visual","basis":"Bloque hueco documentado. Apariencia mineral clara para distinguir el cerramiento; no confirma un revoco ni su espesor.","physicalMaterialUnchanged":true} | ARQ-OF-20260710 · Arquitectura A101 / p. 3, A103 / p. 5, A106 / p. 8; A301Cuadro de materiales | Dimensiones contrastadas con los planos; reconstrucción geométrica a partir de documentación de diseño. | 0.2 | Muros segmentados con huecos reales para puertas y ventanas. | Envolvente exterior controlada por la planta de arquitectura; no se han modelado individualmente todas las capas de acabado. | Registro de líneas del PDF general, envolvente de 20 × 10 m; eje local 1 al norte y acceso del lado A al oeste. Estimación de trabajo de implantación de ±0,15 m, pendiente de CAD; no constituye una precisión topográfica garantizada. | Arquitectura | ARQ-OF-20260710 · Arquitectura A101 / p. 3, A103 / p. 5, A106 / p. 8; A301Cuadro de materiales | 285.95 | Arquitectura | Fábrica de bloques · acabado mineral claro | block_masonry | [0.843137,0.823529,0.772549] | 0.96 | 0 | Bloque hueco documentado. Apariencia mineral clara para distinguir el cerramiento; no confirma un revoco ni su espesor. | Arquitectura; BIM · Arquitectura | El plano general de 2026-07-31 mantiene el edificio de oficinas de 200 m², mientras documentación anterior indica su supresión. Se conserva lo dibujado, pendiente de confirmación de la propiedad y del equipo de diseño.
Edificio de oficinas · Fábrica de bloques huecos de hormigón de 200 mm · eje B · tramo 03 | Planos de arquitectura del edificio de oficinas | Bloque hueco de hormigón de árido ligero | 0.7 × 0.2 × 1.1 | 288.25 | 289.35 | 0.154 | office_0125 | yes | 0.293479 | 0.720717 | 1.1 | 2.26 | 0.154 | office | Edificio de oficinas | {"name":"Bloque hueco de hormigón de árido ligero","source":"ARQ-OF-20260710 · Arquitectura A101 / p. 3, A103 / p. 5, A106 / p. 8; A301Cuadro de materiales ","status":"known"} | {"documented":[{"label":"Espesor del muro","value":0.2,"unit":"m","source":"ARQ-OF-20260710 · Arquitectura A101 / p. 3, A103 / p. 5, A106 / p. 8; A301Cuadro de materiales ","status":"documentado"}],"geometry":[{"label":"Dimensiones de la caja local del elemento (X, Y, Z)","value":"0.7 × 0.2 × 1.1","unit":"m","source":"Malla triangulada del elemento en ejes locales del edificio","status":"derivado"},{"label":"Cota mínima absoluta de la malla","value":288.25,"unit":"m","source":"Malla de proyecto y origen altimétrico 285 m","status":"derivado"},{"label":"Cota máxima absoluta de la malla","value":289.35,"unit":"m","source":"Malla de proyecto y origen altimétrico 285 m","status":"derivado"},{"label":"Volumen geométrico bruto","value":0.154,"unit":"m³","source":"Malla cerrada del elemento","status":"derivado"}],"notes":["Las dimensiones documentadas proceden de anotaciones o cuadros; la caja y el volumen se calculan a partir de la malla.","El volumen es exclusivamente geométrico y bruto; no representa una medición neta de material ni una cantidad de compra."]} | {"documentId":"ARQ-OF-20260710","title":"Planos de arquitectura del edificio de oficinas","date":"2026-07-10","sheet":"Arquitectura A101 / p. 3, A103 / p. 5, A106 / p. 8; A301Cuadro de materiales "} | ["El plano general de 2026-07-31 mantiene el edificio de oficinas de 200 m², mientras documentación anterior indica su supresión. Se conserva lo dibujado, pendiente de confirmación de la propiedad y del equipo de diseño.","Envolvente exterior controlada por la planta de arquitectura; no se han modelado individualmente todas las capas de acabado.","Registro de líneas del PDF general, envolvente de 20 × 10 m; eje local 1 al norte y acceso del lado A al oeste. Estimación de trabajo de implantación de ±0,15 m, pendiente de CAD; no constituye una precisión topográfica garantizada."] | {"horizontalStatus":"derivado","verticalStatus":"derivado","baseElevationM":285.95,"note":"Registro de líneas del PDF general, envolvente de 20 × 10 m; eje local 1 al norte y acceso del lado A al oeste. Estimación de trabajo de implantación de ±0,15 m, pendiente de CAD; no constituye una precisión topográfica garantizada."} | {"Pset_WallCommon":{"IsExternal":{"value":true,"source":"ARQ-OF-20260710 · A101, A103 y alzados; elemento de la envolvente exterior identificada en planta","status":"known"}}} | {"boundingBoxM":{"min":[27.155964,90.862312,3.25],"max":[27.449443,91.583029,4.35]},"extentsM":[0.293479,0.720717,1.1],"meshSurfaceM2":2.260001,"meshVolumeM3":0.154,"closedSolid":true,"basis":"Geometría triangulada releída del IFC; envolventes y magnitudes no contractuales."} | {"material":true,"document":true,"quantities":true,"containerGuid":"3ztlotcerHPueDgxP84R6z","containerName":"Planta baja"} | {"id":"architecture","name":"Arquitectura"} | {"profileId":"block_masonry","name":"Fábrica de bloques · acabado mineral claro","materialName":"Bloque hueco de hormigón de árido ligero","physicalMaterialStatus":"known","physicalMaterialSource":"ARQ-OF-20260710 · Arquitectura A101 / p. 3, A103 / p. 5, A106 / p. 8; A301Cuadro de materiales ","appearanceStatus":"criterio_visual","appearanceBasis":"Bloque hueco documentado. Apariencia mineral clara para distinguir el cerramiento; no confirma un revoco ni su espesor.","note":"La apariencia gráfica no modifica ni confirma la especificación física del material."} | {"elementId":"office_0125","ifcGuid":"3J7typfeDMEhDPXKmXQNrZ","ifcClass":"IfcWall","buildingId":"office","buildingName":"Edificio de oficinas","sourceDocumentId":"ARQ-OF-20260710","sourceRepresentationKind":"documentary_mesh"} | {"layerId":"architecture","layerName":"Arquitectura","role":"Muro","basis":"Clasificación por función del elemento; no modifica las especificaciones documentales."} | architecture | {"profileId":"block_masonry","name":"Fábrica de bloques · acabado mineral claro","status":"criterio_visual","basis":"Bloque hueco documentado. Apariencia mineral clara para distinguir el cerramiento; no confirma un revoco ni su espesor.","physicalMaterialUnchanged":true} | ARQ-OF-20260710 · Arquitectura A101 / p. 3, A103 / p. 5, A106 / p. 8; A301Cuadro de materiales | Dimensiones contrastadas con los planos; reconstrucción geométrica a partir de documentación de diseño. | 0.2 | Muros segmentados con huecos reales para puertas y ventanas. | Envolvente exterior controlada por la planta de arquitectura; no se han modelado individualmente todas las capas de acabado. | Registro de líneas del PDF general, envolvente de 20 × 10 m; eje local 1 al norte y acceso del lado A al oeste. Estimación de trabajo de implantación de ±0,15 m, pendiente de CAD; no constituye una precisión topográfica garantizada. | Arquitectura | ARQ-OF-20260710 · Arquitectura A101 / p. 3, A103 / p. 5, A106 / p. 8; A301Cuadro de materiales | 285.95 | Arquitectura | Fábrica de bloques · acabado mineral claro | block_masonry | [0.843137,0.823529,0.772549] | 0.96 | 0 | Bloque hueco documentado. Apariencia mineral clara para distinguir el cerramiento; no confirma un revoco ni su espesor. | Arquitectura; BIM · Arquitectura | El plano general de 2026-07-31 mantiene el edificio de oficinas de 200 m², mientras documentación anterior indica su supresión. Se conserva lo dibujado, pendiente de confirmación de la propiedad y del equipo de diseño.
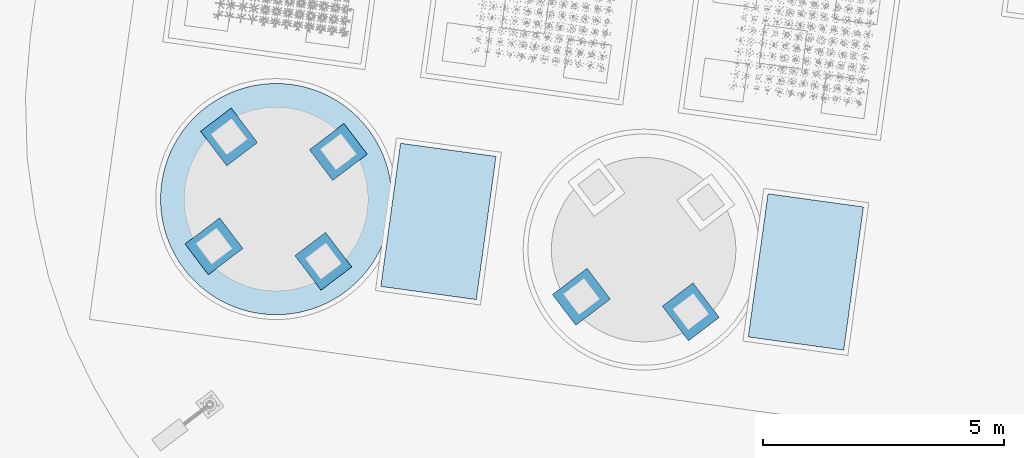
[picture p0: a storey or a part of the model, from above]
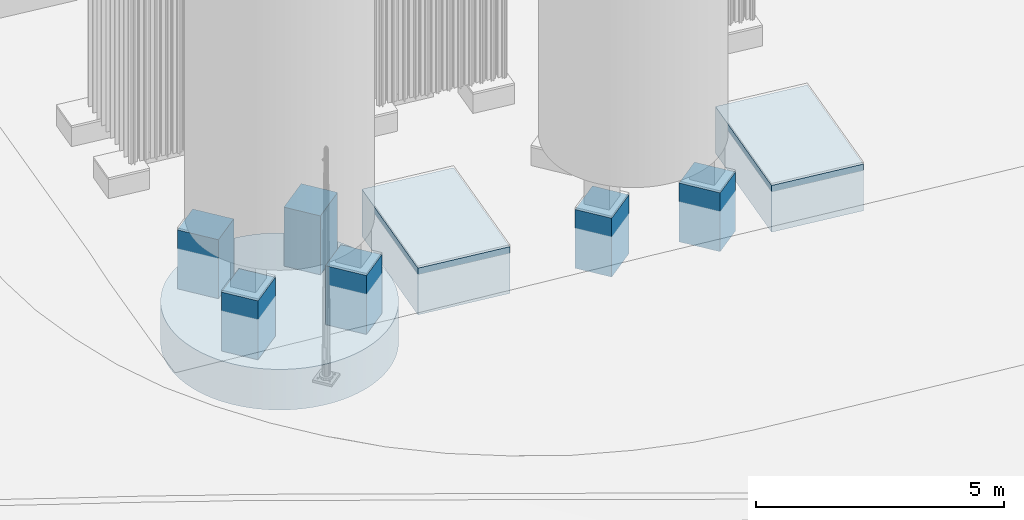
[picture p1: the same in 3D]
Properties of the parts of a building model (IFC4), part 124 of 134

# IfcWall (187)
Name | Document | Material = JH_Trazabilidad, Material = name | Dimensiones de la caja local del elemento (X, Y, Z) | Cota mínima absoluta de la malla (m) | Cota máxima absoluta de la malla (m) | Volumen geométrico bruto (m3) = Volumen geométrico (m³) | Reference = Identificador del elemento = Identificador | IsExternal | ExtensionX (m) | ExtensionY (m) | ExtensionZ (m) | SuperficieDeLaMalla (m2) | VolumenGeometrico (m3) = GrossVolume (m3) | buildingId | buildingName = Edificio | material | dimensions | JH_InformacionBIM, source = DocumentoFuente | issues = IncidenciasPendientes | positioning = PosicionYEstado | commonProperties | geometryMetrics | ifcAssociations | visualLayer | materialAppearance | visualizationIdentity | classification | layerId = IdentificadorCapa | appearance | Planos de referencia | Base geométrica | Espesor del muro (m) = Espesor del muro (m) | Tratamiento de los huecos | Representación de los acabados | Estado de la implantación | Disciplina | Referencia del material = JH_EvidenciaDeMaterial, source | Cota de planta baja terminada (m) | Capa BIM = NombreCapa | Acabado de visualización = Acabado | Perfil | ColorRGB | Rugosidad | Metallicidad | Referencia | Group | Discrepancia entre versiones
Edificio de oficinas · Fábrica de bloques huecos de hormigón de 200 mm · eje B · tramo 14 | Planos de arquitectura del edificio de oficinas | Bloque hueco de hormigón de árido ligero | 0.9 × 0.2 × 1.2 | 287.05 | 288.25 | 0.216 | office_0136 | yes | 0.32072 | 0.918854 | 1.2 | 3 | 0.216 | office | Edificio de oficinas | {"name":"Bloque hueco de hormigón de árido ligero","source":"ARQ-OF-20260710 · Arquitectura A101 / p. 3, A103 / p. 5, A106 / p. 8; A301Cuadro de materiales ","status":"known"} | {"documented":[{"label":"Espesor del muro","value":0.2,"unit":"m","source":"ARQ-OF-20260710 · Arquitectura A101 / p. 3, A103 / p. 5, A106 / p. 8; A301Cuadro de materiales ","status":"documentado"}],"geometry":[{"label":"Dimensiones de la caja local del elemento (X, Y, Z)","value":"0.9 × 0.2 × 1.2","unit":"m","source":"Malla triangulada del elemento en ejes locales del edificio","status":"derivado"},{"label":"Cota mínima absoluta de la malla","value":287.05,"unit":"m","source":"Malla de proyecto y origen altimétrico 285 m","status":"derivado"},{"label":"Cota máxima absoluta de la malla","value":288.25,"unit":"m","source":"Malla de proyecto y origen altimétrico 285 m","status":"derivado"},{"label":"Volumen geométrico bruto","value":0.216,"unit":"m³","source":"Malla cerrada del elemento","status":"derivado"}],"notes":["Las dimensiones documentadas proceden de anotaciones o cuadros; la caja y el volumen se calculan a partir de la malla.","El volumen es exclusivamente geométrico y bruto; no representa una medición neta de material ni una cantidad de compra."]} | {"documentId":"ARQ-OF-20260710","title":"Planos de arquitectura del edificio de oficinas","date":"2026-07-10","sheet":"Arquitectura A101 / p. 3, A103 / p. 5, A106 / p. 8; A301Cuadro de materiales "} | ["El plano general de 2026-07-31 mantiene el edificio de oficinas de 200 m², mientras documentación anterior indica su supresión. Se conserva lo dibujado, pendiente de confirmación de la propiedad y del equipo de diseño.","Envolvente exterior controlada por la planta de arquitectura; no se han modelado individualmente todas las capas de acabado.","Registro de líneas del PDF general, envolvente de 20 × 10 m; eje local 1 al norte y acceso del lado A al oeste. Estimación de trabajo de implantación de ±0,15 m, pendiente de CAD; no constituye una precisión topográfica garantizada."] | {"horizontalStatus":"derivado","verticalStatus":"derivado","baseElevationM":285.95,"note":"Registro de líneas del PDF general, envolvente de 20 × 10 m; eje local 1 al norte y acceso del lado A al oeste. Estimación de trabajo de implantación de ±0,15 m, pendiente de CAD; no constituye una precisión topográfica garantizada."} | {"Pset_WallCommon":{"IsExternal":{"value":true,"source":"ARQ-OF-20260710 · A101, A103 y alzados; elemento de la envolvente exterior identificada en planta","status":"known"}}} | {"boundingBoxM":{"min":[26.66563,87.295861,2.05],"max":[26.98635,88.214715,3.25]},"extentsM":[0.32072,0.918854,1.2],"meshSurfaceM2":3.0,"meshVolumeM3":0.216,"closedSolid":true,"basis":"Geometría triangulada releída del IFC; envolventes y magnitudes no contractuales."} | {"material":true,"document":true,"quantities":true,"containerGuid":"3ztlotcerHPueDgxP84R6z","containerName":"Planta baja"} | {"id":"architecture","name":"Arquitectura"} | {"profileId":"block_masonry","name":"Fábrica de bloques · acabado mineral claro","materialName":"Bloque hueco de hormigón de árido ligero","physicalMaterialStatus":"known","physicalMaterialSource":"ARQ-OF-20260710 · Arquitectura A101 / p. 3, A103 / p. 5, A106 / p. 8; A301Cuadro de materiales ","appearanceStatus":"criterio_visual","appearanceBasis":"Bloque hueco documentado. Apariencia mineral clara para distinguir el cerramiento; no confirma un revoco ni su espesor.","note":"La apariencia gráfica no modifica ni confirma la especificación física del material."} | {"elementId":"office_0136","ifcGuid":"09RcX2xQbPB8F5uN$43J5W","ifcClass":"IfcWall","buildingId":"office","buildingName":"Edificio de oficinas","sourceDocumentId":"ARQ-OF-20260710","sourceRepresentationKind":"documentary_mesh"} | {"layerId":"architecture","layerName":"Arquitectura","role":"Muro","basis":"Clasificación por función del elemento; no modifica las especificaciones documentales."} | architecture | {"profileId":"block_masonry","name":"Fábrica de bloques · acabado mineral claro","status":"criterio_visual","basis":"Bloque hueco documentado. Apariencia mineral clara para distinguir el cerramiento; no confirma un revoco ni su espesor.","physicalMaterialUnchanged":true} | ARQ-OF-20260710 · Arquitectura A101 / p. 3, A103 / p. 5, A106 / p. 8; A301Cuadro de materiales | Dimensiones contrastadas con los planos; reconstrucción geométrica a partir de documentación de diseño. | 0.2 | Muros segmentados con huecos reales para puertas y ventanas. | Envolvente exterior controlada por la planta de arquitectura; no se han modelado individualmente todas las capas de acabado. | Registro de líneas del PDF general, envolvente de 20 × 10 m; eje local 1 al norte y acceso del lado A al oeste. Estimación de trabajo de implantación de ±0,15 m, pendiente de CAD; no constituye una precisión topográfica garantizada. | Arquitectura | ARQ-OF-20260710 · Arquitectura A101 / p. 3, A103 / p. 5, A106 / p. 8; A301Cuadro de materiales | 285.95 | Arquitectura | Fábrica de bloques · acabado mineral claro | block_masonry | [0.843137,0.823529,0.772549] | 0.96 | 0 | Bloque hueco documentado. Apariencia mineral clara para distinguir el cerramiento; no confirma un revoco ni su espesor. | Arquitectura; BIM · Arquitectura | El plano general de 2026-07-31 mantiene el edificio de oficinas de 200 m², mientras documentación anterior indica su supresión. Se conserva lo dibujado, pendiente de confirmación de la propiedad y del equipo de diseño.
Edificio de oficinas · Fábrica de bloques huecos de hormigón de 200 mm · eje B · tramo 15 | Planos de arquitectura del edificio de oficinas | Bloque hueco de hormigón de árido ligero | 0.9 × 0.2 × 1.1 | 288.25 | 289.35 | 0.198 | office_0137 | yes | 0.32072 | 0.918854 | 1.1 | 2.78 | 0.198 | office | Edificio de oficinas | {"name":"Bloque hueco de hormigón de árido ligero","source":"ARQ-OF-20260710 · Arquitectura A101 / p. 3, A103 / p. 5, A106 / p. 8; A301Cuadro de materiales ","status":"known"} | {"documented":[{"label":"Espesor del muro","value":0.2,"unit":"m","source":"ARQ-OF-20260710 · Arquitectura A101 / p. 3, A103 / p. 5, A106 / p. 8; A301Cuadro de materiales ","status":"documentado"}],"geometry":[{"label":"Dimensiones de la caja local del elemento (X, Y, Z)","value":"0.9 × 0.2 × 1.1","unit":"m","source":"Malla triangulada del elemento en ejes locales del edificio","status":"derivado"},{"label":"Cota mínima absoluta de la malla","value":288.25,"unit":"m","source":"Malla de proyecto y origen altimétrico 285 m","status":"derivado"},{"label":"Cota máxima absoluta de la malla","value":289.35,"unit":"m","source":"Malla de proyecto y origen altimétrico 285 m","status":"derivado"},{"label":"Volumen geométrico bruto","value":0.198,"unit":"m³","source":"Malla cerrada del elemento","status":"derivado"}],"notes":["Las dimensiones documentadas proceden de anotaciones o cuadros; la caja y el volumen se calculan a partir de la malla.","El volumen es exclusivamente geométrico y bruto; no representa una medición neta de material ni una cantidad de compra."]} | {"documentId":"ARQ-OF-20260710","title":"Planos de arquitectura del edificio de oficinas","date":"2026-07-10","sheet":"Arquitectura A101 / p. 3, A103 / p. 5, A106 / p. 8; A301Cuadro de materiales "} | ["El plano general de 2026-07-31 mantiene el edificio de oficinas de 200 m², mientras documentación anterior indica su supresión. Se conserva lo dibujado, pendiente de confirmación de la propiedad y del equipo de diseño.","Envolvente exterior controlada por la planta de arquitectura; no se han modelado individualmente todas las capas de acabado.","Registro de líneas del PDF general, envolvente de 20 × 10 m; eje local 1 al norte y acceso del lado A al oeste. Estimación de trabajo de implantación de ±0,15 m, pendiente de CAD; no constituye una precisión topográfica garantizada."] | {"horizontalStatus":"derivado","verticalStatus":"derivado","baseElevationM":285.95,"note":"Registro de líneas del PDF general, envolvente de 20 × 10 m; eje local 1 al norte y acceso del lado A al oeste. Estimación de trabajo de implantación de ±0,15 m, pendiente de CAD; no constituye una precisión topográfica garantizada."} | {"Pset_WallCommon":{"IsExternal":{"value":true,"source":"ARQ-OF-20260710 · A101, A103 y alzados; elemento de la envolvente exterior identificada en planta","status":"known"}}} | {"boundingBoxM":{"min":[26.66563,87.295861,3.25],"max":[26.98635,88.214715,4.35]},"extentsM":[0.32072,0.918854,1.1],"meshSurfaceM2":2.78,"meshVolumeM3":0.198,"closedSolid":true,"basis":"Geometría triangulada releída del IFC; envolventes y magnitudes no contractuales."} | {"material":true,"document":true,"quantities":true,"containerGuid":"3ztlotcerHPueDgxP84R6z","containerName":"Planta baja"} | {"id":"architecture","name":"Arquitectura"} | {"profileId":"block_masonry","name":"Fábrica de bloques · acabado mineral claro","materialName":"Bloque hueco de hormigón de árido ligero","physicalMaterialStatus":"known","physicalMaterialSource":"ARQ-OF-20260710 · Arquitectura A101 / p. 3, A103 / p. 5, A106 / p. 8; A301Cuadro de materiales ","appearanceStatus":"criterio_visual","appearanceBasis":"Bloque hueco documentado. Apariencia mineral clara para distinguir el cerramiento; no confirma un revoco ni su espesor.","note":"La apariencia gráfica no modifica ni confirma la especificación física del material."} | {"elementId":"office_0137","ifcGuid":"1nn2zPyqnQbPD6fHSSuSYh","ifcClass":"IfcWall","buildingId":"office","buildingName":"Edificio de oficinas","sourceDocumentId":"ARQ-OF-20260710","sourceRepresentationKind":"documentary_mesh"} | {"layerId":"architecture","layerName":"Arquitectura","role":"Muro","basis":"Clasificación por función del elemento; no modifica las especificaciones documentales."} | architecture | {"profileId":"block_masonry","name":"Fábrica de bloques · acabado mineral claro","status":"criterio_visual","basis":"Bloque hueco documentado. Apariencia mineral clara para distinguir el cerramiento; no confirma un revoco ni su espesor.","physicalMaterialUnchanged":true} | ARQ-OF-20260710 · Arquitectura A101 / p. 3, A103 / p. 5, A106 / p. 8; A301Cuadro de materiales | Dimensiones contrastadas con los planos; reconstrucción geométrica a partir de documentación de diseño. | 0.2 | Muros segmentados con huecos reales para puertas y ventanas. | Envolvente exterior controlada por la planta de arquitectura; no se han modelado individualmente todas las capas de acabado. | Registro de líneas del PDF general, envolvente de 20 × 10 m; eje local 1 al norte y acceso del lado A al oeste. Estimación de trabajo de implantación de ±0,15 m, pendiente de CAD; no constituye una precisión topográfica garantizada. | Arquitectura | ARQ-OF-20260710 · Arquitectura A101 / p. 3, A103 / p. 5, A106 / p. 8; A301Cuadro de materiales | 285.95 | Arquitectura | Fábrica de bloques · acabado mineral claro | block_masonry | [0.843137,0.823529,0.772549] | 0.96 | 0 | Bloque hueco documentado. Apariencia mineral clara para distinguir el cerramiento; no confirma un revoco ni su espesor. | Arquitectura; BIM · Arquitectura | El plano general de 2026-07-31 mantiene el edificio de oficinas de 200 m², mientras documentación anterior indica su supresión. Se conserva lo dibujado, pendiente de confirmación de la propiedad y del equipo de diseño.
Edificio de oficinas · Fábrica de bloques huecos de hormigón de 200 mm · eje B · tramo 16 | Planos de arquitectura del edificio de oficinas | Bloque hueco de hormigón de árido ligero | 0.9 × 0.2 × 1.6 | 289.35 | 290.95 | 0.288 | office_0138 | yes | 0.32072 | 0.918854 | 1.6 | 3.88 | 0.288 | office | Edificio de oficinas | {"name":"Bloque hueco de hormigón de árido ligero","source":"ARQ-OF-20260710 · Arquitectura A101 / p. 3, A103 / p. 5, A106 / p. 8; A301Cuadro de materiales ","status":"known"} | {"documented":[{"label":"Espesor del muro","value":0.2,"unit":"m","source":"ARQ-OF-20260710 · Arquitectura A101 / p. 3, A103 / p. 5, A106 / p. 8; A301Cuadro de materiales ","status":"documentado"}],"geometry":[{"label":"Dimensiones de la caja local del elemento (X, Y, Z)","value":"0.9 × 0.2 × 1.6","unit":"m","source":"Malla triangulada del elemento en ejes locales del edificio","status":"derivado"},{"label":"Cota mínima absoluta de la malla","value":289.35,"unit":"m","source":"Malla de proyecto y origen altimétrico 285 m","status":"derivado"},{"label":"Cota máxima absoluta de la malla","value":290.95,"unit":"m","source":"Malla de proyecto y origen altimétrico 285 m","status":"derivado"},{"label":"Volumen geométrico bruto","value":0.288,"unit":"m³","source":"Malla cerrada del elemento","status":"derivado"}],"notes":["Las dimensiones documentadas proceden de anotaciones o cuadros; la caja y el volumen se calculan a partir de la malla.","El volumen es exclusivamente geométrico y bruto; no representa una medición neta de material ni una cantidad de compra."]} | {"documentId":"ARQ-OF-20260710","title":"Planos de arquitectura del edificio de oficinas","date":"2026-07-10","sheet":"Arquitectura A101 / p. 3, A103 / p. 5, A106 / p. 8; A301Cuadro de materiales "} | ["El plano general de 2026-07-31 mantiene el edificio de oficinas de 200 m², mientras documentación anterior indica su supresión. Se conserva lo dibujado, pendiente de confirmación de la propiedad y del equipo de diseño.","Envolvente exterior controlada por la planta de arquitectura; no se han modelado individualmente todas las capas de acabado.","Registro de líneas del PDF general, envolvente de 20 × 10 m; eje local 1 al norte y acceso del lado A al oeste. Estimación de trabajo de implantación de ±0,15 m, pendiente de CAD; no constituye una precisión topográfica garantizada."] | {"horizontalStatus":"derivado","verticalStatus":"derivado","baseElevationM":285.95,"note":"Registro de líneas del PDF general, envolvente de 20 × 10 m; eje local 1 al norte y acceso del lado A al oeste. Estimación de trabajo de implantación de ±0,15 m, pendiente de CAD; no constituye una precisión topográfica garantizada."} | {"Pset_WallCommon":{"IsExternal":{"value":true,"source":"ARQ-OF-20260710 · A101, A103 y alzados; elemento de la envolvente exterior identificada en planta","status":"known"}}} | {"boundingBoxM":{"min":[26.66563,87.295861,4.35],"max":[26.98635,88.214715,5.95]},"extentsM":[0.32072,0.918854,1.6],"meshSurfaceM2":3.88,"meshVolumeM3":0.288,"closedSolid":true,"basis":"Geometría triangulada releída del IFC; envolventes y magnitudes no contractuales."} | {"material":true,"document":true,"quantities":true,"containerGuid":"3ztlotcerHPueDgxP84R6z","containerName":"Planta baja"} | {"id":"architecture","name":"Arquitectura"} | {"profileId":"block_masonry","name":"Fábrica de bloques · acabado mineral claro","materialName":"Bloque hueco de hormigón de árido ligero","physicalMaterialStatus":"known","physicalMaterialSource":"ARQ-OF-20260710 · Arquitectura A101 / p. 3, A103 / p. 5, A106 / p. 8; A301Cuadro de materiales ","appearanceStatus":"criterio_visual","appearanceBasis":"Bloque hueco documentado. Apariencia mineral clara para distinguir el cerramiento; no confirma un revoco ni su espesor.","note":"La apariencia gráfica no modifica ni confirma la especificación física del material."} | {"elementId":"office_0138","ifcGuid":"3sSLWFHwXJWPqtjCyQOfnL","ifcClass":"IfcWall","buildingId":"office","buildingName":"Edificio de oficinas","sourceDocumentId":"ARQ-OF-20260710","sourceRepresentationKind":"documentary_mesh"} | {"layerId":"architecture","layerName":"Arquitectura","role":"Muro","basis":"Clasificación por función del elemento; no modifica las especificaciones documentales."} | architecture | {"profileId":"block_masonry","name":"Fábrica de bloques · acabado mineral claro","status":"criterio_visual","basis":"Bloque hueco documentado. Apariencia mineral clara para distinguir el cerramiento; no confirma un revoco ni su espesor.","physicalMaterialUnchanged":true} | ARQ-OF-20260710 · Arquitectura A101 / p. 3, A103 / p. 5, A106 / p. 8; A301Cuadro de materiales | Dimensiones contrastadas con los planos; reconstrucción geométrica a partir de documentación de diseño. | 0.2 | Muros segmentados con huecos reales para puertas y ventanas. | Envolvente exterior controlada por la planta de arquitectura; no se han modelado individualmente todas las capas de acabado. | Registro de líneas del PDF general, envolvente de 20 × 10 m; eje local 1 al norte y acceso del lado A al oeste. Estimación de trabajo de implantación de ±0,15 m, pendiente de CAD; no constituye una precisión topográfica garantizada. | Arquitectura | ARQ-OF-20260710 · Arquitectura A101 / p. 3, A103 / p. 5, A106 / p. 8; A301Cuadro de materiales | 285.95 | Arquitectura | Fábrica de bloques · acabado mineral claro | block_masonry | [0.843137,0.823529,0.772549] | 0.96 | 0 | Bloque hueco documentado. Apariencia mineral clara para distinguir el cerramiento; no confirma un revoco ni su espesor. | Arquitectura; BIM · Arquitectura | El plano general de 2026-07-31 mantiene el edificio de oficinas de 200 m², mientras documentación anterior indica su supresión. Se conserva lo dibujado, pendiente de confirmación de la propiedad y del equipo de diseño.
Edificio de oficinas · Fábrica de bloques huecos de hormigón de 200 mm · eje B · tramo 17 | Planos de arquitectura del edificio de oficinas | Bloque hueco de hormigón de árido ligero | 0.9 × 0.2 × 1.1 | 285.95 | 287.05 | 0.198 | office_0139 | yes | 0.320719 | 0.918854 | 1.1 | 2.78 | 0.198 | office | Edificio de oficinas | {"name":"Bloque hueco de hormigón de árido ligero","source":"ARQ-OF-20260710 · Arquitectura A101 / p. 3, A103 / p. 5, A106 / p. 8; A301Cuadro de materiales ","status":"known"} | {"documented":[{"label":"Espesor del muro","value":0.2,"unit":"m","source":"ARQ-OF-20260710 · Arquitectura A101 / p. 3, A103 / p. 5, A106 / p. 8; A301Cuadro de materiales ","status":"documentado"}],"geometry":[{"label":"Dimensiones de la caja local del elemento (X, Y, Z)","value":"0.9 × 0.2 × 1.1","unit":"m","source":"Malla triangulada del elemento en ejes locales del edificio","status":"derivado"},{"label":"Cota mínima absoluta de la malla","value":285.95,"unit":"m","source":"Malla de proyecto y origen altimétrico 285 m","status":"derivado"},{"label":"Cota máxima absoluta de la malla","value":287.05,"unit":"m","source":"Malla de proyecto y origen altimétrico 285 m","status":"derivado"},{"label":"Volumen geométrico bruto","value":0.198,"unit":"m³","source":"Malla cerrada del elemento","status":"derivado"}],"notes":["Las dimensiones documentadas proceden de anotaciones o cuadros; la caja y el volumen se calculan a partir de la malla.","El volumen es exclusivamente geométrico y bruto; no representa una medición neta de material ni una cantidad de compra."]} | {"documentId":"ARQ-OF-20260710","title":"Planos de arquitectura del edificio de oficinas","date":"2026-07-10","sheet":"Arquitectura A101 / p. 3, A103 / p. 5, A106 / p. 8; A301Cuadro de materiales "} | ["El plano general de 2026-07-31 mantiene el edificio de oficinas de 200 m², mientras documentación anterior indica su supresión. Se conserva lo dibujado, pendiente de confirmación de la propiedad y del equipo de diseño.","Envolvente exterior controlada por la planta de arquitectura; no se han modelado individualmente todas las capas de acabado.","Registro de líneas del PDF general, envolvente de 20 × 10 m; eje local 1 al norte y acceso del lado A al oeste. Estimación de trabajo de implantación de ±0,15 m, pendiente de CAD; no constituye una precisión topográfica garantizada."] | {"horizontalStatus":"derivado","verticalStatus":"derivado","baseElevationM":285.95,"note":"Registro de líneas del PDF general, envolvente de 20 × 10 m; eje local 1 al norte y acceso del lado A al oeste. Estimación de trabajo de implantación de ±0,15 m, pendiente de CAD; no constituye una precisión topográfica garantizada."} | {"Pset_WallCommon":{"IsExternal":{"value":true,"source":"ARQ-OF-20260710 · A101, A103 y alzados; elemento de la envolvente exterior identificada en planta","status":"known"}}} | {"boundingBoxM":{"min":[26.543047,86.404248,0.95],"max":[26.863766,87.323102,2.05]},"extentsM":[0.320719,0.918854,1.1],"meshSurfaceM2":2.78,"meshVolumeM3":0.198,"closedSolid":true,"basis":"Geometría triangulada releída del IFC; envolventes y magnitudes no contractuales."} | {"material":true,"document":true,"quantities":true,"containerGuid":"3ztlotcerHPueDgxP84R6z","containerName":"Planta baja"} | {"id":"architecture","name":"Arquitectura"} | {"profileId":"block_masonry","name":"Fábrica de bloques · acabado mineral claro","materialName":"Bloque hueco de hormigón de árido ligero","physicalMaterialStatus":"known","physicalMaterialSource":"ARQ-OF-20260710 · Arquitectura A101 / p. 3, A103 / p. 5, A106 / p. 8; A301Cuadro de materiales ","appearanceStatus":"criterio_visual","appearanceBasis":"Bloque hueco documentado. Apariencia mineral clara para distinguir el cerramiento; no confirma un revoco ni su espesor.","note":"La apariencia gráfica no modifica ni confirma la especificación física del material."} | {"elementId":"office_0139","ifcGuid":"3d8Hwc_KPJf9ug4Ma1$Qv1","ifcClass":"IfcWall","buildingId":"office","buildingName":"Edificio de oficinas","sourceDocumentId":"ARQ-OF-20260710","sourceRepresentationKind":"documentary_mesh"} | {"layerId":"architecture","layerName":"Arquitectura","role":"Muro","basis":"Clasificación por función del elemento; no modifica las especificaciones documentales."} | architecture | {"profileId":"block_masonry","name":"Fábrica de bloques · acabado mineral claro","status":"criterio_visual","basis":"Bloque hueco documentado. Apariencia mineral clara para distinguir el cerramiento; no confirma un revoco ni su espesor.","physicalMaterialUnchanged":true} | ARQ-OF-20260710 · Arquitectura A101 / p. 3, A103 / p. 5, A106 / p. 8; A301Cuadro de materiales | Dimensiones contrastadas con los planos; reconstrucción geométrica a partir de documentación de diseño. | 0.2 | Muros segmentados con huecos reales para puertas y ventanas. | Envolvente exterior controlada por la planta de arquitectura; no se han modelado individualmente todas las capas de acabado. | Registro de líneas del PDF general, envolvente de 20 × 10 m; eje local 1 al norte y acceso del lado A al oeste. Estimación de trabajo de implantación de ±0,15 m, pendiente de CAD; no constituye una precisión topográfica garantizada. | Arquitectura | ARQ-OF-20260710 · Arquitectura A101 / p. 3, A103 / p. 5, A106 / p. 8; A301Cuadro de materiales | 285.95 | Arquitectura | Fábrica de bloques · acabado mineral claro | block_masonry | [0.843137,0.823529,0.772549] | 0.96 | 0 | Bloque hueco documentado. Apariencia mineral clara para distinguir el cerramiento; no confirma un revoco ni su espesor. | Arquitectura; BIM · Arquitectura | El plano general de 2026-07-31 mantiene el edificio de oficinas de 200 m², mientras documentación anterior indica su supresión. Se conserva lo dibujado, pendiente de confirmación de la propiedad y del equipo de diseño.
Edificio de oficinas · Fábrica de bloques huecos de hormigón de 200 mm · eje B · tramo 18 | Planos de arquitectura del edificio de oficinas | Bloque hueco de hormigón de árido ligero | 0.9 × 0.2 × 1.6 | 289.35 | 290.95 | 0.288 | office_0140 | yes | 0.320719 | 0.918854 | 1.6 | 3.88 | 0.288 | office | Edificio de oficinas | {"name":"Bloque hueco de hormigón de árido ligero","source":"ARQ-OF-20260710 · Arquitectura A101 / p. 3, A103 / p. 5, A106 / p. 8; A301Cuadro de materiales ","status":"known"} | {"documented":[{"label":"Espesor del muro","value":0.2,"unit":"m","source":"ARQ-OF-20260710 · Arquitectura A101 / p. 3, A103 / p. 5, A106 / p. 8; A301Cuadro de materiales ","status":"documentado"}],"geometry":[{"label":"Dimensiones de la caja local del elemento (X, Y, Z)","value":"0.9 × 0.2 × 1.6","unit":"m","source":"Malla triangulada del elemento en ejes locales del edificio","status":"derivado"},{"label":"Cota mínima absoluta de la malla","value":289.35,"unit":"m","source":"Malla de proyecto y origen altimétrico 285 m","status":"derivado"},{"label":"Cota máxima absoluta de la malla","value":290.95,"unit":"m","source":"Malla de proyecto y origen altimétrico 285 m","status":"derivado"},{"label":"Volumen geométrico bruto","value":0.288,"unit":"m³","source":"Malla cerrada del elemento","status":"derivado"}],"notes":["Las dimensiones documentadas proceden de anotaciones o cuadros; la caja y el volumen se calculan a partir de la malla.","El volumen es exclusivamente geométrico y bruto; no representa una medición neta de material ni una cantidad de compra."]} | {"documentId":"ARQ-OF-20260710","title":"Planos de arquitectura del edificio de oficinas","date":"2026-07-10","sheet":"Arquitectura A101 / p. 3, A103 / p. 5, A106 / p. 8; A301Cuadro de materiales "} | ["El plano general de 2026-07-31 mantiene el edificio de oficinas de 200 m², mientras documentación anterior indica su supresión. Se conserva lo dibujado, pendiente de confirmación de la propiedad y del equipo de diseño.","Envolvente exterior controlada por la planta de arquitectura; no se han modelado individualmente todas las capas de acabado.","Registro de líneas del PDF general, envolvente de 20 × 10 m; eje local 1 al norte y acceso del lado A al oeste. Estimación de trabajo de implantación de ±0,15 m, pendiente de CAD; no constituye una precisión topográfica garantizada."] | {"horizontalStatus":"derivado","verticalStatus":"derivado","baseElevationM":285.95,"note":"Registro de líneas del PDF general, envolvente de 20 × 10 m; eje local 1 al norte y acceso del lado A al oeste. Estimación de trabajo de implantación de ±0,15 m, pendiente de CAD; no constituye una precisión topográfica garantizada."} | {"Pset_WallCommon":{"IsExternal":{"value":true,"source":"ARQ-OF-20260710 · A101, A103 y alzados; elemento de la envolvente exterior identificada en planta","status":"known"}}} | {"boundingBoxM":{"min":[26.543047,86.404248,4.35],"max":[26.863766,87.323102,5.95]},"extentsM":[0.320719,0.918854,1.6],"meshSurfaceM2":3.88,"meshVolumeM3":0.288,"closedSolid":true,"basis":"Geometría triangulada releída del IFC; envolventes y magnitudes no contractuales."} | {"material":true,"document":true,"quantities":true,"containerGuid":"3ztlotcerHPueDgxP84R6z","containerName":"Planta baja"} | {"id":"architecture","name":"Arquitectura"} | {"profileId":"block_masonry","name":"Fábrica de bloques · acabado mineral claro","materialName":"Bloque hueco de hormigón de árido ligero","physicalMaterialStatus":"known","physicalMaterialSource":"ARQ-OF-20260710 · Arquitectura A101 / p. 3, A103 / p. 5, A106 / p. 8; A301Cuadro de materiales ","appearanceStatus":"criterio_visual","appearanceBasis":"Bloque hueco documentado. Apariencia mineral clara para distinguir el cerramiento; no confirma un revoco ni su espesor.","note":"La apariencia gráfica no modifica ni confirma la especificación física del material."} | {"elementId":"office_0140","ifcGuid":"2lF1ljC2rHLvtTULXPP2Lr","ifcClass":"IfcWall","buildingId":"office","buildingName":"Edificio de oficinas","sourceDocumentId":"ARQ-OF-20260710","sourceRepresentationKind":"documentary_mesh"} | {"layerId":"architecture","layerName":"Arquitectura","role":"Muro","basis":"Clasificación por función del elemento; no modifica las especificaciones documentales."} | architecture | {"profileId":"block_masonry","name":"Fábrica de bloques · acabado mineral claro","status":"criterio_visual","basis":"Bloque hueco documentado. Apariencia mineral clara para distinguir el cerramiento; no confirma un revoco ni su espesor.","physicalMaterialUnchanged":true} | ARQ-OF-20260710 · Arquitectura A101 / p. 3, A103 / p. 5, A106 / p. 8; A301Cuadro de materiales | Dimensiones contrastadas con los planos; reconstrucción geométrica a partir de documentación de diseño. | 0.2 | Muros segmentados con huecos reales para puertas y ventanas. | Envolvente exterior controlada por la planta de arquitectura; no se han modelado individualmente todas las capas de acabado. | Registro de líneas del PDF general, envolvente de 20 × 10 m; eje local 1 al norte y acceso del lado A al oeste. Estimación de trabajo de implantación de ±0,15 m, pendiente de CAD; no constituye una precisión topográfica garantizada. | Arquitectura | ARQ-OF-20260710 · Arquitectura A101 / p. 3, A103 / p. 5, A106 / p. 8; A301Cuadro de materiales | 285.95 | Arquitectura | Fábrica de bloques · acabado mineral claro | block_masonry | [0.843137,0.823529,0.772549] | 0.96 | 0 | Bloque hueco documentado. Apariencia mineral clara para distinguir el cerramiento; no confirma un revoco ni su espesor. | Arquitectura; BIM · Arquitectura | El plano general de 2026-07-31 mantiene el edificio de oficinas de 200 m², mientras documentación anterior indica su supresión. Se conserva lo dibujado, pendiente de confirmación de la propiedad y del equipo de diseño.
Edificio de oficinas · Fábrica de bloques huecos de hormigón de 200 mm · eje B · tramo 19 | Planos de arquitectura del edificio de oficinas | Bloque hueco de hormigón de árido ligero | 0.9 × 0.2 × 1.1 | 285.95 | 287.05 | 0.198 | office_0141 | yes | 0.32072 | 0.918853 | 1.1 | 2.78 | 0.198 | office | Edificio de oficinas | {"name":"Bloque hueco de hormigón de árido ligero","source":"ARQ-OF-20260710 · Arquitectura A101 / p. 3, A103 / p. 5, A106 / p. 8; A301Cuadro de materiales ","status":"known"} | {"documented":[{"label":"Espesor del muro","value":0.2,"unit":"m","source":"ARQ-OF-20260710 · Arquitectura A101 / p. 3, A103 / p. 5, A106 / p. 8; A301Cuadro de materiales ","status":"documentado"}],"geometry":[{"label":"Dimensiones de la caja local del elemento (X, Y, Z)","value":"0.9 × 0.2 × 1.1","unit":"m","source":"Malla triangulada del elemento en ejes locales del edificio","status":"derivado"},{"label":"Cota mínima absoluta de la malla","value":285.95,"unit":"m","source":"Malla de proyecto y origen altimétrico 285 m","status":"derivado"},{"label":"Cota máxima absoluta de la malla","value":287.05,"unit":"m","source":"Malla de proyecto y origen altimétrico 285 m","status":"derivado"},{"label":"Volumen geométrico bruto","value":0.198,"unit":"m³","source":"Malla cerrada del elemento","status":"derivado"}],"notes":["Las dimensiones documentadas proceden de anotaciones o cuadros; la caja y el volumen se calculan a partir de la malla.","El volumen es exclusivamente geométrico y bruto; no representa una medición neta de material ni una cantidad de compra."]} | {"documentId":"ARQ-OF-20260710","title":"Planos de arquitectura del edificio de oficinas","date":"2026-07-10","sheet":"Arquitectura A101 / p. 3, A103 / p. 5, A106 / p. 8; A301Cuadro de materiales "} | ["El plano general de 2026-07-31 mantiene el edificio de oficinas de 200 m², mientras documentación anterior indica su supresión. Se conserva lo dibujado, pendiente de confirmación de la propiedad y del equipo de diseño.","Envolvente exterior controlada por la planta de arquitectura; no se han modelado individualmente todas las capas de acabado.","Registro de líneas del PDF general, envolvente de 20 × 10 m; eje local 1 al norte y acceso del lado A al oeste. Estimación de trabajo de implantación de ±0,15 m, pendiente de CAD; no constituye una precisión topográfica garantizada."] | {"horizontalStatus":"derivado","verticalStatus":"derivado","baseElevationM":285.95,"note":"Registro de líneas del PDF general, envolvente de 20 × 10 m; eje local 1 al norte y acceso del lado A al oeste. Estimación de trabajo de implantación de ±0,15 m, pendiente de CAD; no constituye una precisión topográfica garantizada."} | {"Pset_WallCommon":{"IsExternal":{"value":true,"source":"ARQ-OF-20260710 · A101, A103 y alzados; elemento de la envolvente exterior identificada en planta","status":"known"}}} | {"boundingBoxM":{"min":[26.420463,85.512636,0.95],"max":[26.741183,86.431489,2.05]},"extentsM":[0.32072,0.918853,1.1],"meshSurfaceM2":2.779999,"meshVolumeM3":0.198,"closedSolid":true,"basis":"Geometría triangulada releída del IFC; envolventes y magnitudes no contractuales."} | {"material":true,"document":true,"quantities":true,"containerGuid":"3ztlotcerHPueDgxP84R6z","containerName":"Planta baja"} | {"id":"architecture","name":"Arquitectura"} | {"profileId":"block_masonry","name":"Fábrica de bloques · acabado mineral claro","materialName":"Bloque hueco de hormigón de árido ligero","physicalMaterialStatus":"known","physicalMaterialSource":"ARQ-OF-20260710 · Arquitectura A101 / p. 3, A103 / p. 5, A106 / p. 8; A301Cuadro de materiales ","appearanceStatus":"criterio_visual","appearanceBasis":"Bloque hueco documentado. Apariencia mineral clara para distinguir el cerramiento; no confirma un revoco ni su espesor.","note":"La apariencia gráfica no modifica ni confirma la especificación física del material."} | {"elementId":"office_0141","ifcGuid":"1O4Qa5G2zNPxp9b4jncyTA","ifcClass":"IfcWall","buildingId":"office","buildingName":"Edificio de oficinas","sourceDocumentId":"ARQ-OF-20260710","sourceRepresentationKind":"documentary_mesh"} | {"layerId":"architecture","layerName":"Arquitectura","role":"Muro","basis":"Clasificación por función del elemento; no modifica las especificaciones documentales."} | architecture | {"profileId":"block_masonry","name":"Fábrica de bloques · acabado mineral claro","status":"criterio_visual","basis":"Bloque hueco documentado. Apariencia mineral clara para distinguir el cerramiento; no confirma un revoco ni su espesor.","physicalMaterialUnchanged":true} | ARQ-OF-20260710 · Arquitectura A101 / p. 3, A103 / p. 5, A106 / p. 8; A301Cuadro de materiales | Dimensiones contrastadas con los planos; reconstrucción geométrica a partir de documentación de diseño. | 0.2 | Muros segmentados con huecos reales para puertas y ventanas. | Envolvente exterior controlada por la planta de arquitectura; no se han modelado individualmente todas las capas de acabado. | Registro de líneas del PDF general, envolvente de 20 × 10 m; eje local 1 al norte y acceso del lado A al oeste. Estimación de trabajo de implantación de ±0,15 m, pendiente de CAD; no constituye una precisión topográfica garantizada. | Arquitectura | ARQ-OF-20260710 · Arquitectura A101 / p. 3, A103 / p. 5, A106 / p. 8; A301Cuadro de materiales | 285.95 | Arquitectura | Fábrica de bloques · acabado mineral claro | block_masonry | [0.843137,0.823529,0.772549] | 0.96 | 0 | Bloque hueco documentado. Apariencia mineral clara para distinguir el cerramiento; no confirma un revoco ni su espesor. | Arquitectura; BIM · Arquitectura | El plano general de 2026-07-31 mantiene el edificio de oficinas de 200 m², mientras documentación anterior indica su supresión. Se conserva lo dibujado, pendiente de confirmación de la propiedad y del equipo de diseño.
Edificio de oficinas · Fábrica de bloques huecos de hormigón de 200 mm · eje B · tramo 20 | Planos de arquitectura del edificio de oficinas | Bloque hueco de hormigón de árido ligero | 0.9 × 0.2 × 1.2 | 287.05 | 288.25 | 0.216 | office_0142 | yes | 0.32072 | 0.918853 | 1.2 | 3 | 0.216 | office | Edificio de oficinas | {"name":"Bloque hueco de hormigón de árido ligero","source":"ARQ-OF-20260710 · Arquitectura A101 / p. 3, A103 / p. 5, A106 / p. 8; A301Cuadro de materiales ","status":"known"} | {"documented":[{"label":"Espesor del muro","value":0.2,"unit":"m","source":"ARQ-OF-20260710 · Arquitectura A101 / p. 3, A103 / p. 5, A106 / p. 8; A301Cuadro de materiales ","status":"documentado"}],"geometry":[{"label":"Dimensiones de la caja local del elemento (X, Y, Z)","value":"0.9 × 0.2 × 1.2","unit":"m","source":"Malla triangulada del elemento en ejes locales del edificio","status":"derivado"},{"label":"Cota mínima absoluta de la malla","value":287.05,"unit":"m","source":"Malla de proyecto y origen altimétrico 285 m","status":"derivado"},{"label":"Cota máxima absoluta de la malla","value":288.25,"unit":"m","source":"Malla de proyecto y origen altimétrico 285 m","status":"derivado"},{"label":"Volumen geométrico bruto","value":0.216,"unit":"m³","source":"Malla cerrada del elemento","status":"derivado"}],"notes":["Las dimensiones documentadas proceden de anotaciones o cuadros; la caja y el volumen se calculan a partir de la malla.","El volumen es exclusivamente geométrico y bruto; no representa una medición neta de material ni una cantidad de compra."]} | {"documentId":"ARQ-OF-20260710","title":"Planos de arquitectura del edificio de oficinas","date":"2026-07-10","sheet":"Arquitectura A101 / p. 3, A103 / p. 5, A106 / p. 8; A301Cuadro de materiales "} | ["El plano general de 2026-07-31 mantiene el edificio de oficinas de 200 m², mientras documentación anterior indica su supresión. Se conserva lo dibujado, pendiente de confirmación de la propiedad y del equipo de diseño.","Envolvente exterior controlada por la planta de arquitectura; no se han modelado individualmente todas las capas de acabado.","Registro de líneas del PDF general, envolvente de 20 × 10 m; eje local 1 al norte y acceso del lado A al oeste. Estimación de trabajo de implantación de ±0,15 m, pendiente de CAD; no constituye una precisión topográfica garantizada."] | {"horizontalStatus":"derivado","verticalStatus":"derivado","baseElevationM":285.95,"note":"Registro de líneas del PDF general, envolvente de 20 × 10 m; eje local 1 al norte y acceso del lado A al oeste. Estimación de trabajo de implantación de ±0,15 m, pendiente de CAD; no constituye una precisión topográfica garantizada."} | {"Pset_WallCommon":{"IsExternal":{"value":true,"source":"ARQ-OF-20260710 · A101, A103 y alzados; elemento de la envolvente exterior identificada en planta","status":"known"}}} | {"boundingBoxM":{"min":[26.420463,85.512636,2.05],"max":[26.741183,86.431489,3.25]},"extentsM":[0.32072,0.918853,1.2],"meshSurfaceM2":2.999999,"meshVolumeM3":0.216,"closedSolid":true,"basis":"Geometría triangulada releída del IFC; envolventes y magnitudes no contractuales."} | {"material":true,"document":true,"quantities":true,"containerGuid":"3ztlotcerHPueDgxP84R6z","containerName":"Planta baja"} | {"id":"architecture","name":"Arquitectura"} | {"profileId":"block_masonry","name":"Fábrica de bloques · acabado mineral claro","materialName":"Bloque hueco de hormigón de árido ligero","physicalMaterialStatus":"known","physicalMaterialSource":"ARQ-OF-20260710 · Arquitectura A101 / p. 3, A103 / p. 5, A106 / p. 8; A301Cuadro de materiales ","appearanceStatus":"criterio_visual","appearanceBasis":"Bloque hueco documentado. Apariencia mineral clara para distinguir el cerramiento; no confirma un revoco ni su espesor.","note":"La apariencia gráfica no modifica ni confirma la especificación física del material."} | {"elementId":"office_0142","ifcGuid":"0nQWZeYinVfOt56Ig0rW84","ifcClass":"IfcWall","buildingId":"office","buildingName":"Edificio de oficinas","sourceDocumentId":"ARQ-OF-20260710","sourceRepresentationKind":"documentary_mesh"} | {"layerId":"architecture","layerName":"Arquitectura","role":"Muro","basis":"Clasificación por función del elemento; no modifica las especificaciones documentales."} | architecture | {"profileId":"block_masonry","name":"Fábrica de bloques · acabado mineral claro","status":"criterio_visual","basis":"Bloque hueco documentado. Apariencia mineral clara para distinguir el cerramiento; no confirma un revoco ni su espesor.","physicalMaterialUnchanged":true} | ARQ-OF-20260710 · Arquitectura A101 / p. 3, A103 / p. 5, A106 / p. 8; A301Cuadro de materiales | Dimensiones contrastadas con los planos; reconstrucción geométrica a partir de documentación de diseño. | 0.2 | Muros segmentados con huecos reales para puertas y ventanas. | Envolvente exterior controlada por la planta de arquitectura; no se han modelado individualmente todas las capas de acabado. | Registro de líneas del PDF general, envolvente de 20 × 10 m; eje local 1 al norte y acceso del lado A al oeste. Estimación de trabajo de implantación de ±0,15 m, pendiente de CAD; no constituye una precisión topográfica garantizada. | Arquitectura | ARQ-OF-20260710 · Arquitectura A101 / p. 3, A103 / p. 5, A106 / p. 8; A301Cuadro de materiales | 285.95 | Arquitectura | Fábrica de bloques · acabado mineral claro | block_masonry | [0.843137,0.823529,0.772549] | 0.96 | 0 | Bloque hueco documentado. Apariencia mineral clara para distinguir el cerramiento; no confirma un revoco ni su espesor. | Arquitectura; BIM · Arquitectura | El plano general de 2026-07-31 mantiene el edificio de oficinas de 200 m², mientras documentación anterior indica su supresión. Se conserva lo dibujado, pendiente de confirmación de la propiedad y del equipo de diseño.
Edificio de oficinas · Fábrica de bloques huecos de hormigón de 200 mm · eje B · tramo 21 | Planos de arquitectura del edificio de oficinas | Bloque hueco de hormigón de árido ligero | 0.9 × 0.2 × 1.1 | 288.25 | 289.35 | 0.198 | office_0143 | yes | 0.32072 | 0.918853 | 1.1 | 2.78 | 0.198 | office | Edificio de oficinas | {"name":"Bloque hueco de hormigón de árido ligero","source":"ARQ-OF-20260710 · Arquitectura A101 / p. 3, A103 / p. 5, A106 / p. 8; A301Cuadro de materiales ","status":"known"} | {"documented":[{"label":"Espesor del muro","value":0.2,"unit":"m","source":"ARQ-OF-20260710 · Arquitectura A101 / p. 3, A103 / p. 5, A106 / p. 8; A301Cuadro de materiales ","status":"documentado"}],"geometry":[{"label":"Dimensiones de la caja local del elemento (X, Y, Z)","value":"0.9 × 0.2 × 1.1","unit":"m","source":"Malla triangulada del elemento en ejes locales del edificio","status":"derivado"},{"label":"Cota mínima absoluta de la malla","value":288.25,"unit":"m","source":"Malla de proyecto y origen altimétrico 285 m","status":"derivado"},{"label":"Cota máxima absoluta de la malla","value":289.35,"unit":"m","source":"Malla de proyecto y origen altimétrico 285 m","status":"derivado"},{"label":"Volumen geométrico bruto","value":0.198,"unit":"m³","source":"Malla cerrada del elemento","status":"derivado"}],"notes":["Las dimensiones documentadas proceden de anotaciones o cuadros; la caja y el volumen se calculan a partir de la malla.","El volumen es exclusivamente geométrico y bruto; no representa una medición neta de material ni una cantidad de compra."]} | {"documentId":"ARQ-OF-20260710","title":"Planos de arquitectura del edificio de oficinas","date":"2026-07-10","sheet":"Arquitectura A101 / p. 3, A103 / p. 5, A106 / p. 8; A301Cuadro de materiales "} | ["El plano general de 2026-07-31 mantiene el edificio de oficinas de 200 m², mientras documentación anterior indica su supresión. Se conserva lo dibujado, pendiente de confirmación de la propiedad y del equipo de diseño.","Envolvente exterior controlada por la planta de arquitectura; no se han modelado individualmente todas las capas de acabado.","Registro de líneas del PDF general, envolvente de 20 × 10 m; eje local 1 al norte y acceso del lado A al oeste. Estimación de trabajo de implantación de ±0,15 m, pendiente de CAD; no constituye una precisión topográfica garantizada."] | {"horizontalStatus":"derivado","verticalStatus":"derivado","baseElevationM":285.95,"note":"Registro de líneas del PDF general, envolvente de 20 × 10 m; eje local 1 al norte y acceso del lado A al oeste. Estimación de trabajo de implantación de ±0,15 m, pendiente de CAD; no constituye una precisión topográfica garantizada."} | {"Pset_WallCommon":{"IsExternal":{"value":true,"source":"ARQ-OF-20260710 · A101, A103 y alzados; elemento de la envolvente exterior identificada en planta","status":"known"}}} | {"boundingBoxM":{"min":[26.420463,85.512636,3.25],"max":[26.741183,86.431489,4.35]},"extentsM":[0.32072,0.918853,1.1],"meshSurfaceM2":2.779999,"meshVolumeM3":0.198,"closedSolid":true,"basis":"Geometría triangulada releída del IFC; envolventes y magnitudes no contractuales."} | {"material":true,"document":true,"quantities":true,"containerGuid":"3ztlotcerHPueDgxP84R6z","containerName":"Planta baja"} | {"id":"architecture","name":"Arquitectura"} | {"profileId":"block_masonry","name":"Fábrica de bloques · acabado mineral claro","materialName":"Bloque hueco de hormigón de árido ligero","physicalMaterialStatus":"known","physicalMaterialSource":"ARQ-OF-20260710 · Arquitectura A101 / p. 3, A103 / p. 5, A106 / p. 8; A301Cuadro de materiales ","appearanceStatus":"criterio_visual","appearanceBasis":"Bloque hueco documentado. Apariencia mineral clara para distinguir el cerramiento; no confirma un revoco ni su espesor.","note":"La apariencia gráfica no modifica ni confirma la especificación física del material."} | {"elementId":"office_0143","ifcGuid":"3_I79eJXzMzPFzYIoXL$Ip","ifcClass":"IfcWall","buildingId":"office","buildingName":"Edificio de oficinas","sourceDocumentId":"ARQ-OF-20260710","sourceRepresentationKind":"documentary_mesh"} | {"layerId":"architecture","layerName":"Arquitectura","role":"Muro","basis":"Clasificación por función del elemento; no modifica las especificaciones documentales."} | architecture | {"profileId":"block_masonry","name":"Fábrica de bloques · acabado mineral claro","status":"criterio_visual","basis":"Bloque hueco documentado. Apariencia mineral clara para distinguir el cerramiento; no confirma un revoco ni su espesor.","physicalMaterialUnchanged":true} | ARQ-OF-20260710 · Arquitectura A101 / p. 3, A103 / p. 5, A106 / p. 8; A301Cuadro de materiales | Dimensiones contrastadas con los planos; reconstrucción geométrica a partir de documentación de diseño. | 0.2 | Muros segmentados con huecos reales para puertas y ventanas. | Envolvente exterior controlada por la planta de arquitectura; no se han modelado individualmente todas las capas de acabado. | Registro de líneas del PDF general, envolvente de 20 × 10 m; eje local 1 al norte y acceso del lado A al oeste. Estimación de trabajo de implantación de ±0,15 m, pendiente de CAD; no constituye una precisión topográfica garantizada. | Arquitectura | ARQ-OF-20260710 · Arquitectura A101 / p. 3, A103 / p. 5, A106 / p. 8; A301Cuadro de materiales | 285.95 | Arquitectura | Fábrica de bloques · acabado mineral claro | block_masonry | [0.843137,0.823529,0.772549] | 0.96 | 0 | Bloque hueco documentado. Apariencia mineral clara para distinguir el cerramiento; no confirma un revoco ni su espesor. | Arquitectura; BIM · Arquitectura | El plano general de 2026-07-31 mantiene el edificio de oficinas de 200 m², mientras documentación anterior indica su supresión. Se conserva lo dibujado, pendiente de confirmación de la propiedad y del equipo de diseño.
Edificio de oficinas · Fábrica de bloques huecos de hormigón de 200 mm · eje B · tramo 22 | Planos de arquitectura del edificio de oficinas | Bloque hueco de hormigón de árido ligero | 0.9 × 0.2 × 1.6 | 289.35 | 290.95 | 0.288 | office_0144 | yes | 0.32072 | 0.918853 | 1.6 | 3.88 | 0.288 | office | Edificio de oficinas | {"name":"Bloque hueco de hormigón de árido ligero","source":"ARQ-OF-20260710 · Arquitectura A101 / p. 3, A103 / p. 5, A106 / p. 8; A301Cuadro de materiales ","status":"known"} | {"documented":[{"label":"Espesor del muro","value":0.2,"unit":"m","source":"ARQ-OF-20260710 · Arquitectura A101 / p. 3, A103 / p. 5, A106 / p. 8; A301Cuadro de materiales ","status":"documentado"}],"geometry":[{"label":"Dimensiones de la caja local del elemento (X, Y, Z)","value":"0.9 × 0.2 × 1.6","unit":"m","source":"Malla triangulada del elemento en ejes locales del edificio","status":"derivado"},{"label":"Cota mínima absoluta de la malla","value":289.35,"unit":"m","source":"Malla de proyecto y origen altimétrico 285 m","status":"derivado"},{"label":"Cota máxima absoluta de la malla","value":290.95,"unit":"m","source":"Malla de proyecto y origen altimétrico 285 m","status":"derivado"},{"label":"Volumen geométrico bruto","value":0.288,"unit":"m³","source":"Malla cerrada del elemento","status":"derivado"}],"notes":["Las dimensiones documentadas proceden de anotaciones o cuadros; la caja y el volumen se calculan a partir de la malla.","El volumen es exclusivamente geométrico y bruto; no representa una medición neta de material ni una cantidad de compra."]} | {"documentId":"ARQ-OF-20260710","title":"Planos de arquitectura del edificio de oficinas","date":"2026-07-10","sheet":"Arquitectura A101 / p. 3, A103 / p. 5, A106 / p. 8; A301Cuadro de materiales "} | ["El plano general de 2026-07-31 mantiene el edificio de oficinas de 200 m², mientras documentación anterior indica su supresión. Se conserva lo dibujado, pendiente de confirmación de la propiedad y del equipo de diseño.","Envolvente exterior controlada por la planta de arquitectura; no se han modelado individualmente todas las capas de acabado.","Registro de líneas del PDF general, envolvente de 20 × 10 m; eje local 1 al norte y acceso del lado A al oeste. Estimación de trabajo de implantación de ±0,15 m, pendiente de CAD; no constituye una precisión topográfica garantizada."] | {"horizontalStatus":"derivado","verticalStatus":"derivado","baseElevationM":285.95,"note":"Registro de líneas del PDF general, envolvente de 20 × 10 m; eje local 1 al norte y acceso del lado A al oeste. Estimación de trabajo de implantación de ±0,15 m, pendiente de CAD; no constituye una precisión topográfica garantizada."} | {"Pset_WallCommon":{"IsExternal":{"value":true,"source":"ARQ-OF-20260710 · A101, A103 y alzados; elemento de la envolvente exterior identificada en planta","status":"known"}}} | {"boundingBoxM":{"min":[26.420463,85.512636,4.35],"max":[26.741183,86.431489,5.95]},"extentsM":[0.32072,0.918853,1.6],"meshSurfaceM2":3.879998,"meshVolumeM3":0.288,"closedSolid":true,"basis":"Geometría triangulada releída del IFC; envolventes y magnitudes no contractuales."} | {"material":true,"document":true,"quantities":true,"containerGuid":"3ztlotcerHPueDgxP84R6z","containerName":"Planta baja"} | {"id":"architecture","name":"Arquitectura"} | {"profileId":"block_masonry","name":"Fábrica de bloques · acabado mineral claro","materialName":"Bloque hueco de hormigón de árido ligero","physicalMaterialStatus":"known","physicalMaterialSource":"ARQ-OF-20260710 · Arquitectura A101 / p. 3, A103 / p. 5, A106 / p. 8; A301Cuadro de materiales ","appearanceStatus":"criterio_visual","appearanceBasis":"Bloque hueco documentado. Apariencia mineral clara para distinguir el cerramiento; no confirma un revoco ni su espesor.","note":"La apariencia gráfica no modifica ni confirma la especificación física del material."} | {"elementId":"office_0144","ifcGuid":"00oMuTT_vKO8B6wrsuzczH","ifcClass":"IfcWall","buildingId":"office","buildingName":"Edificio de oficinas","sourceDocumentId":"ARQ-OF-20260710","sourceRepresentationKind":"documentary_mesh"} | {"layerId":"architecture","layerName":"Arquitectura","role":"Muro","basis":"Clasificación por función del elemento; no modifica las especificaciones documentales."} | architecture | {"profileId":"block_masonry","name":"Fábrica de bloques · acabado mineral claro","status":"criterio_visual","basis":"Bloque hueco documentado. Apariencia mineral clara para distinguir el cerramiento; no confirma un revoco ni su espesor.","physicalMaterialUnchanged":true} | ARQ-OF-20260710 · Arquitectura A101 / p. 3, A103 / p. 5, A106 / p. 8; A301Cuadro de materiales | Dimensiones contrastadas con los planos; reconstrucción geométrica a partir de documentación de diseño. | 0.2 | Muros segmentados con huecos reales para puertas y ventanas. | Envolvente exterior controlada por la planta de arquitectura; no se han modelado individualmente todas las capas de acabado. | Registro de líneas del PDF general, envolvente de 20 × 10 m; eje local 1 al norte y acceso del lado A al oeste. Estimación de trabajo de implantación de ±0,15 m, pendiente de CAD; no constituye una precisión topográfica garantizada. | Arquitectura | ARQ-OF-20260710 · Arquitectura A101 / p. 3, A103 / p. 5, A106 / p. 8; A301Cuadro de materiales | 285.95 | Arquitectura | Fábrica de bloques · acabado mineral claro | block_masonry | [0.843137,0.823529,0.772549] | 0.96 | 0 | Bloque hueco documentado. Apariencia mineral clara para distinguir el cerramiento; no confirma un revoco ni su espesor. | Arquitectura; BIM · Arquitectura | El plano general de 2026-07-31 mantiene el edificio de oficinas de 200 m², mientras documentación anterior indica su supresión. Se conserva lo dibujado, pendiente de confirmación de la propiedad y del equipo de diseño.
Edificio de oficinas · Fábrica de bloques huecos de hormigón de 200 mm · eje B · tramo 23 | Planos de arquitectura del edificio de oficinas | Bloque hueco de hormigón de árido ligero | 0.9 × 0.2 × 1.1 | 285.95 | 287.05 | 0.198 | office_0145 | yes | 0.320719 | 0.918853 | 1.1 | 2.78 | 0.198 | office | Edificio de oficinas | {"name":"Bloque hueco de hormigón de árido ligero","source":"ARQ-OF-20260710 · Arquitectura A101 / p. 3, A103 / p. 5, A106 / p. 8; A301Cuadro de materiales ","status":"known"} | {"documented":[{"label":"Espesor del muro","value":0.2,"unit":"m","source":"ARQ-OF-20260710 · Arquitectura A101 / p. 3, A103 / p. 5, A106 / p. 8; A301Cuadro de materiales ","status":"documentado"}],"geometry":[{"label":"Dimensiones de la caja local del elemento (X, Y, Z)","value":"0.9 × 0.2 × 1.1","unit":"m","source":"Malla triangulada del elemento en ejes locales del edificio","status":"derivado"},{"label":"Cota mínima absoluta de la malla","value":285.95,"unit":"m","source":"Malla de proyecto y origen altimétrico 285 m","status":"derivado"},{"label":"Cota máxima absoluta de la malla","value":287.05,"unit":"m","source":"Malla de proyecto y origen altimétrico 285 m","status":"derivado"},{"label":"Volumen geométrico bruto","value":0.198,"unit":"m³","source":"Malla cerrada del elemento","status":"derivado"}],"notes":["Las dimensiones documentadas proceden de anotaciones o cuadros; la caja y el volumen se calculan a partir de la malla.","El volumen es exclusivamente geométrico y bruto; no representa una medición neta de material ni una cantidad de compra."]} | {"documentId":"ARQ-OF-20260710","title":"Planos de arquitectura del edificio de oficinas","date":"2026-07-10","sheet":"Arquitectura A101 / p. 3, A103 / p. 5, A106 / p. 8; A301Cuadro de materiales "} | ["El plano general de 2026-07-31 mantiene el edificio de oficinas de 200 m², mientras documentación anterior indica su supresión. Se conserva lo dibujado, pendiente de confirmación de la propiedad y del equipo de diseño.","Envolvente exterior controlada por la planta de arquitectura; no se han modelado individualmente todas las capas de acabado.","Registro de líneas del PDF general, envolvente de 20 × 10 m; eje local 1 al norte y acceso del lado A al oeste. Estimación de trabajo de implantación de ±0,15 m, pendiente de CAD; no constituye una precisión topográfica garantizada."] | {"horizontalStatus":"derivado","verticalStatus":"derivado","baseElevationM":285.95,"note":"Registro de líneas del PDF general, envolvente de 20 × 10 m; eje local 1 al norte y acceso del lado A al oeste. Estimación de trabajo de implantación de ±0,15 m, pendiente de CAD; no constituye una precisión topográfica garantizada."} | {"Pset_WallCommon":{"IsExternal":{"value":true,"source":"ARQ-OF-20260710 · A101, A103 y alzados; elemento de la envolvente exterior identificada en planta","status":"known"}}} | {"boundingBoxM":{"min":[26.29788,84.621023,0.95],"max":[26.618599,85.539876,2.05]},"extentsM":[0.320719,0.918853,1.1],"meshSurfaceM2":2.779998,"meshVolumeM3":0.198,"closedSolid":true,"basis":"Geometría triangulada releída del IFC; envolventes y magnitudes no contractuales."} | {"material":true,"document":true,"quantities":true,"containerGuid":"3ztlotcerHPueDgxP84R6z","containerName":"Planta baja"} | {"id":"architecture","name":"Arquitectura"} | {"profileId":"block_masonry","name":"Fábrica de bloques · acabado mineral claro","materialName":"Bloque hueco de hormigón de árido ligero","physicalMaterialStatus":"known","physicalMaterialSource":"ARQ-OF-20260710 · Arquitectura A101 / p. 3, A103 / p. 5, A106 / p. 8; A301Cuadro de materiales ","appearanceStatus":"criterio_visual","appearanceBasis":"Bloque hueco documentado. Apariencia mineral clara para distinguir el cerramiento; no confirma un revoco ni su espesor.","note":"La apariencia gráfica no modifica ni confirma la especificación física del material."} | {"elementId":"office_0145","ifcGuid":"2771DDuobKA94_2Il7va5S","ifcClass":"IfcWall","buildingId":"office","buildingName":"Edificio de oficinas","sourceDocumentId":"ARQ-OF-20260710","sourceRepresentationKind":"documentary_mesh"} | {"layerId":"architecture","layerName":"Arquitectura","role":"Muro","basis":"Clasificación por función del elemento; no modifica las especificaciones documentales."} | architecture | {"profileId":"block_masonry","name":"Fábrica de bloques · acabado mineral claro","status":"criterio_visual","basis":"Bloque hueco documentado. Apariencia mineral clara para distinguir el cerramiento; no confirma un revoco ni su espesor.","physicalMaterialUnchanged":true} | ARQ-OF-20260710 · Arquitectura A101 / p. 3, A103 / p. 5, A106 / p. 8; A301Cuadro de materiales | Dimensiones contrastadas con los planos; reconstrucción geométrica a partir de documentación de diseño. | 0.2 | Muros segmentados con huecos reales para puertas y ventanas. | Envolvente exterior controlada por la planta de arquitectura; no se han modelado individualmente todas las capas de acabado. | Registro de líneas del PDF general, envolvente de 20 × 10 m; eje local 1 al norte y acceso del lado A al oeste. Estimación de trabajo de implantación de ±0,15 m, pendiente de CAD; no constituye una precisión topográfica garantizada. | Arquitectura | ARQ-OF-20260710 · Arquitectura A101 / p. 3, A103 / p. 5, A106 / p. 8; A301Cuadro de materiales | 285.95 | Arquitectura | Fábrica de bloques · acabado mineral claro | block_masonry | [0.843137,0.823529,0.772549] | 0.96 | 0 | Bloque hueco documentado. Apariencia mineral clara para distinguir el cerramiento; no confirma un revoco ni su espesor. | Arquitectura; BIM · Arquitectura | El plano general de 2026-07-31 mantiene el edificio de oficinas de 200 m², mientras documentación anterior indica su supresión. Se conserva lo dibujado, pendiente de confirmación de la propiedad y del equipo de diseño.
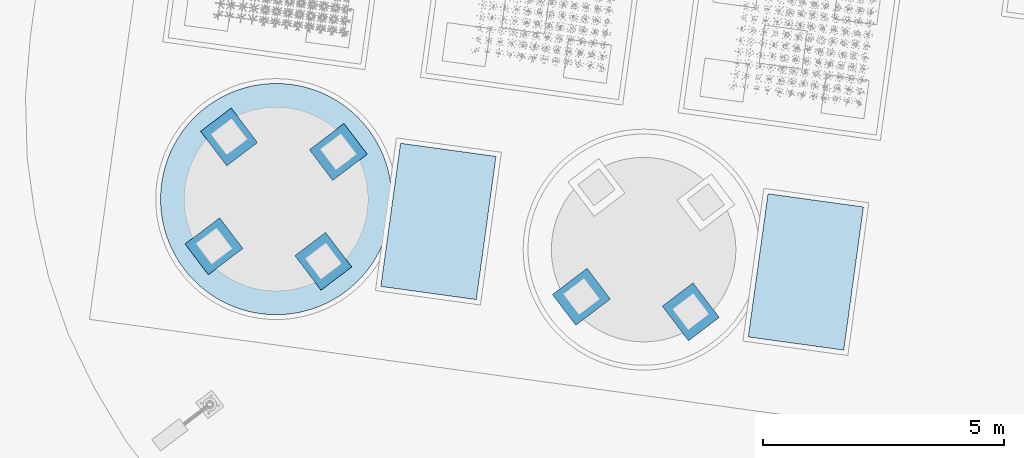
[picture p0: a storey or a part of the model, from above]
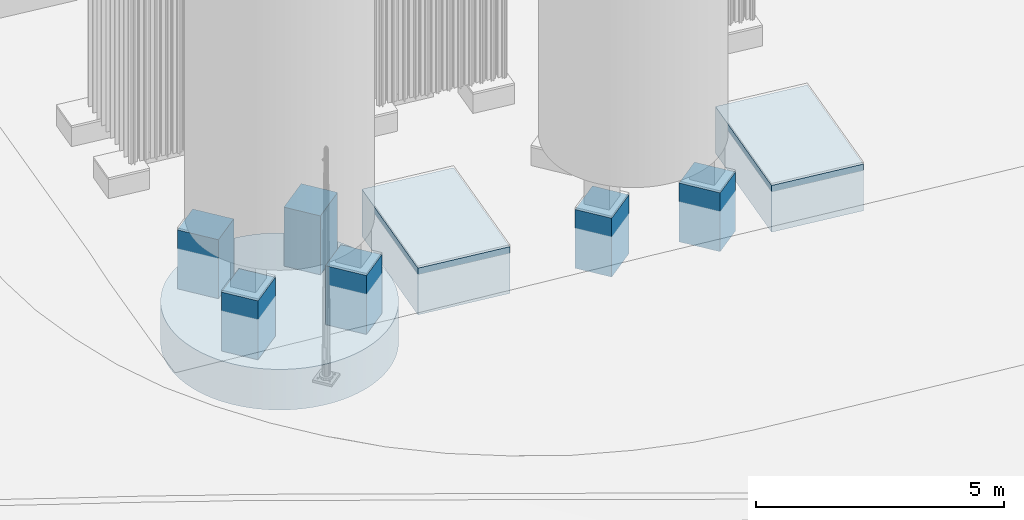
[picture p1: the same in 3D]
Properties of the parts of a building model (IFC4), part 125 of 134

# IfcWall (187)
Name | Document | Material = JH_Trazabilidad, Material = name | Dimensiones de la caja local del elemento (X, Y, Z) | Cota mínima absoluta de la malla (m) | Cota máxima absoluta de la malla (m) | Volumen geométrico bruto (m3) = Volumen geométrico (m³) | Reference = Identificador del elemento = Identificador | IsExternal | ExtensionX (m) | ExtensionY (m) | ExtensionZ (m) | SuperficieDeLaMalla (m2) | VolumenGeometrico (m3) = GrossVolume (m3) | buildingId | buildingName = Edificio | material | dimensions | JH_InformacionBIM, source = DocumentoFuente | issues = IncidenciasPendientes | positioning = PosicionYEstado | commonProperties | geometryMetrics | ifcAssociations | visualLayer | materialAppearance | visualizationIdentity | classification | layerId = IdentificadorCapa | appearance | Planos de referencia | Base geométrica | Espesor del muro (m) = Espesor del muro (m) | Tratamiento de los huecos | Representación de los acabados | Estado de la implantación | Disciplina | Referencia del material = JH_EvidenciaDeMaterial, source | Cota de planta baja terminada (m) | Capa BIM = NombreCapa | Acabado de visualización = Acabado | Perfil | ColorRGB | Rugosidad | Metallicidad | Referencia | Group | Discrepancia entre versiones
Edificio de oficinas · Fábrica de bloques huecos de hormigón de 200 mm · eje B · tramo 24 | Planos de arquitectura del edificio de oficinas | Bloque hueco de hormigón de árido ligero | 0.9 × 0.2 × 1.6 | 289.35 | 290.95 | 0.288 | office_0146 | yes | 0.320719 | 0.918853 | 1.6 | 3.88 | 0.288 | office | Edificio de oficinas | {"name":"Bloque hueco de hormigón de árido ligero","source":"ARQ-OF-20260710 · Arquitectura A101 / p. 3, A103 / p. 5, A106 / p. 8; A301Cuadro de materiales ","status":"known"} | {"documented":[{"label":"Espesor del muro","value":0.2,"unit":"m","source":"ARQ-OF-20260710 · Arquitectura A101 / p. 3, A103 / p. 5, A106 / p. 8; A301Cuadro de materiales ","status":"documentado"}],"geometry":[{"label":"Dimensiones de la caja local del elemento (X, Y, Z)","value":"0.9 × 0.2 × 1.6","unit":"m","source":"Malla triangulada del elemento en ejes locales del edificio","status":"derivado"},{"label":"Cota mínima absoluta de la malla","value":289.35,"unit":"m","source":"Malla de proyecto y origen altimétrico 285 m","status":"derivado"},{"label":"Cota máxima absoluta de la malla","value":290.95,"unit":"m","source":"Malla de proyecto y origen altimétrico 285 m","status":"derivado"},{"label":"Volumen geométrico bruto","value":0.288,"unit":"m³","source":"Malla cerrada del elemento","status":"derivado"}],"notes":["Las dimensiones documentadas proceden de anotaciones o cuadros; la caja y el volumen se calculan a partir de la malla.","El volumen es exclusivamente geométrico y bruto; no representa una medición neta de material ni una cantidad de compra."]} | {"documentId":"ARQ-OF-20260710","title":"Planos de arquitectura del edificio de oficinas","date":"2026-07-10","sheet":"Arquitectura A101 / p. 3, A103 / p. 5, A106 / p. 8; A301Cuadro de materiales "} | ["El plano general de 2026-07-31 mantiene el edificio de oficinas de 200 m², mientras documentación anterior indica su supresión. Se conserva lo dibujado, pendiente de confirmación de la propiedad y del equipo de diseño.","Envolvente exterior controlada por la planta de arquitectura; no se han modelado individualmente todas las capas de acabado.","Registro de líneas del PDF general, envolvente de 20 × 10 m; eje local 1 al norte y acceso del lado A al oeste. Estimación de trabajo de implantación de ±0,15 m, pendiente de CAD; no constituye una precisión topográfica garantizada."] | {"horizontalStatus":"derivado","verticalStatus":"derivado","baseElevationM":285.95,"note":"Registro de líneas del PDF general, envolvente de 20 × 10 m; eje local 1 al norte y acceso del lado A al oeste. Estimación de trabajo de implantación de ±0,15 m, pendiente de CAD; no constituye una precisión topográfica garantizada."} | {"Pset_WallCommon":{"IsExternal":{"value":true,"source":"ARQ-OF-20260710 · A101, A103 y alzados; elemento de la envolvente exterior identificada en planta","status":"known"}}} | {"boundingBoxM":{"min":[26.29788,84.621023,4.35],"max":[26.618599,85.539876,5.95]},"extentsM":[0.320719,0.918853,1.6],"meshSurfaceM2":3.879998,"meshVolumeM3":0.288,"closedSolid":true,"basis":"Geometría triangulada releída del IFC; envolventes y magnitudes no contractuales."} | {"material":true,"document":true,"quantities":true,"containerGuid":"3ztlotcerHPueDgxP84R6z","containerName":"Planta baja"} | {"id":"architecture","name":"Arquitectura"} | {"profileId":"block_masonry","name":"Fábrica de bloques · acabado mineral claro","materialName":"Bloque hueco de hormigón de árido ligero","physicalMaterialStatus":"known","physicalMaterialSource":"ARQ-OF-20260710 · Arquitectura A101 / p. 3, A103 / p. 5, A106 / p. 8; A301Cuadro de materiales ","appearanceStatus":"criterio_visual","appearanceBasis":"Bloque hueco documentado. Apariencia mineral clara para distinguir el cerramiento; no confirma un revoco ni su espesor.","note":"La apariencia gráfica no modifica ni confirma la especificación física del material."} | {"elementId":"office_0146","ifcGuid":"2vRzxquEPGIwEJAqlFnSXT","ifcClass":"IfcWall","buildingId":"office","buildingName":"Edificio de oficinas","sourceDocumentId":"ARQ-OF-20260710","sourceRepresentationKind":"documentary_mesh"} | {"layerId":"architecture","layerName":"Arquitectura","role":"Muro","basis":"Clasificación por función del elemento; no modifica las especificaciones documentales."} | architecture | {"profileId":"block_masonry","name":"Fábrica de bloques · acabado mineral claro","status":"criterio_visual","basis":"Bloque hueco documentado. Apariencia mineral clara para distinguir el cerramiento; no confirma un revoco ni su espesor.","physicalMaterialUnchanged":true} | ARQ-OF-20260710 · Arquitectura A101 / p. 3, A103 / p. 5, A106 / p. 8; A301Cuadro de materiales | Dimensiones contrastadas con los planos; reconstrucción geométrica a partir de documentación de diseño. | 0.2 | Muros segmentados con huecos reales para puertas y ventanas. | Envolvente exterior controlada por la planta de arquitectura; no se han modelado individualmente todas las capas de acabado. | Registro de líneas del PDF general, envolvente de 20 × 10 m; eje local 1 al norte y acceso del lado A al oeste. Estimación de trabajo de implantación de ±0,15 m, pendiente de CAD; no constituye una precisión topográfica garantizada. | Arquitectura | ARQ-OF-20260710 · Arquitectura A101 / p. 3, A103 / p. 5, A106 / p. 8; A301Cuadro de materiales | 285.95 | Arquitectura | Fábrica de bloques · acabado mineral claro | block_masonry | [0.843137,0.823529,0.772549] | 0.96 | 0 | Bloque hueco documentado. Apariencia mineral clara para distinguir el cerramiento; no confirma un revoco ni su espesor. | Arquitectura; BIM · Arquitectura | El plano general de 2026-07-31 mantiene el edificio de oficinas de 200 m², mientras documentación anterior indica su supresión. Se conserva lo dibujado, pendiente de confirmación de la propiedad y del equipo de diseño.
Edificio de oficinas · Fábrica de bloques huecos de hormigón de 200 mm · eje B · tramo 25 | Planos de arquitectura del edificio de oficinas | Bloque hueco de hormigón de árido ligero | 0.9 × 0.2 × 1.1 | 285.95 | 287.05 | 0.198 | office_0147 | yes | 0.32072 | 0.918854 | 1.1 | 2.78 | 0.198 | office | Edificio de oficinas | {"name":"Bloque hueco de hormigón de árido ligero","source":"ARQ-OF-20260710 · Arquitectura A101 / p. 3, A103 / p. 5, A106 / p. 8; A301Cuadro de materiales ","status":"known"} | {"documented":[{"label":"Espesor del muro","value":0.2,"unit":"m","source":"ARQ-OF-20260710 · Arquitectura A101 / p. 3, A103 / p. 5, A106 / p. 8; A301Cuadro de materiales ","status":"documentado"}],"geometry":[{"label":"Dimensiones de la caja local del elemento (X, Y, Z)","value":"0.9 × 0.2 × 1.1","unit":"m","source":"Malla triangulada del elemento en ejes locales del edificio","status":"derivado"},{"label":"Cota mínima absoluta de la malla","value":285.95,"unit":"m","source":"Malla de proyecto y origen altimétrico 285 m","status":"derivado"},{"label":"Cota máxima absoluta de la malla","value":287.05,"unit":"m","source":"Malla de proyecto y origen altimétrico 285 m","status":"derivado"},{"label":"Volumen geométrico bruto","value":0.198,"unit":"m³","source":"Malla cerrada del elemento","status":"derivado"}],"notes":["Las dimensiones documentadas proceden de anotaciones o cuadros; la caja y el volumen se calculan a partir de la malla.","El volumen es exclusivamente geométrico y bruto; no representa una medición neta de material ni una cantidad de compra."]} | {"documentId":"ARQ-OF-20260710","title":"Planos de arquitectura del edificio de oficinas","date":"2026-07-10","sheet":"Arquitectura A101 / p. 3, A103 / p. 5, A106 / p. 8; A301Cuadro de materiales "} | ["El plano general de 2026-07-31 mantiene el edificio de oficinas de 200 m², mientras documentación anterior indica su supresión. Se conserva lo dibujado, pendiente de confirmación de la propiedad y del equipo de diseño.","Envolvente exterior controlada por la planta de arquitectura; no se han modelado individualmente todas las capas de acabado.","Registro de líneas del PDF general, envolvente de 20 × 10 m; eje local 1 al norte y acceso del lado A al oeste. Estimación de trabajo de implantación de ±0,15 m, pendiente de CAD; no constituye una precisión topográfica garantizada."] | {"horizontalStatus":"derivado","verticalStatus":"derivado","baseElevationM":285.95,"note":"Registro de líneas del PDF general, envolvente de 20 × 10 m; eje local 1 al norte y acceso del lado A al oeste. Estimación de trabajo de implantación de ±0,15 m, pendiente de CAD; no constituye una precisión topográfica garantizada."} | {"Pset_WallCommon":{"IsExternal":{"value":true,"source":"ARQ-OF-20260710 · A101, A103 y alzados; elemento de la envolvente exterior identificada en planta","status":"known"}}} | {"boundingBoxM":{"min":[26.175296,83.72941,0.95],"max":[26.496016,84.648264,2.05]},"extentsM":[0.32072,0.918854,1.1],"meshSurfaceM2":2.78,"meshVolumeM3":0.198,"closedSolid":true,"basis":"Geometría triangulada releída del IFC; envolventes y magnitudes no contractuales."} | {"material":true,"document":true,"quantities":true,"containerGuid":"3ztlotcerHPueDgxP84R6z","containerName":"Planta baja"} | {"id":"architecture","name":"Arquitectura"} | {"profileId":"block_masonry","name":"Fábrica de bloques · acabado mineral claro","materialName":"Bloque hueco de hormigón de árido ligero","physicalMaterialStatus":"known","physicalMaterialSource":"ARQ-OF-20260710 · Arquitectura A101 / p. 3, A103 / p. 5, A106 / p. 8; A301Cuadro de materiales ","appearanceStatus":"criterio_visual","appearanceBasis":"Bloque hueco documentado. Apariencia mineral clara para distinguir el cerramiento; no confirma un revoco ni su espesor.","note":"La apariencia gráfica no modifica ni confirma la especificación física del material."} | {"elementId":"office_0147","ifcGuid":"1tAQpXQNPHBOF8v1FoML7n","ifcClass":"IfcWall","buildingId":"office","buildingName":"Edificio de oficinas","sourceDocumentId":"ARQ-OF-20260710","sourceRepresentationKind":"documentary_mesh"} | {"layerId":"architecture","layerName":"Arquitectura","role":"Muro","basis":"Clasificación por función del elemento; no modifica las especificaciones documentales."} | architecture | {"profileId":"block_masonry","name":"Fábrica de bloques · acabado mineral claro","status":"criterio_visual","basis":"Bloque hueco documentado. Apariencia mineral clara para distinguir el cerramiento; no confirma un revoco ni su espesor.","physicalMaterialUnchanged":true} | ARQ-OF-20260710 · Arquitectura A101 / p. 3, A103 / p. 5, A106 / p. 8; A301Cuadro de materiales | Dimensiones contrastadas con los planos; reconstrucción geométrica a partir de documentación de diseño. | 0.2 | Muros segmentados con huecos reales para puertas y ventanas. | Envolvente exterior controlada por la planta de arquitectura; no se han modelado individualmente todas las capas de acabado. | Registro de líneas del PDF general, envolvente de 20 × 10 m; eje local 1 al norte y acceso del lado A al oeste. Estimación de trabajo de implantación de ±0,15 m, pendiente de CAD; no constituye una precisión topográfica garantizada. | Arquitectura | ARQ-OF-20260710 · Arquitectura A101 / p. 3, A103 / p. 5, A106 / p. 8; A301Cuadro de materiales | 285.95 | Arquitectura | Fábrica de bloques · acabado mineral claro | block_masonry | [0.843137,0.823529,0.772549] | 0.96 | 0 | Bloque hueco documentado. Apariencia mineral clara para distinguir el cerramiento; no confirma un revoco ni su espesor. | Arquitectura; BIM · Arquitectura | El plano general de 2026-07-31 mantiene el edificio de oficinas de 200 m², mientras documentación anterior indica su supresión. Se conserva lo dibujado, pendiente de confirmación de la propiedad y del equipo de diseño.
Edificio de oficinas · Fábrica de bloques huecos de hormigón de 200 mm · eje B · tramo 26 | Planos de arquitectura del edificio de oficinas | Bloque hueco de hormigón de árido ligero | 0.9 × 0.2 × 1.2 | 287.05 | 288.25 | 0.216 | office_0148 | yes | 0.32072 | 0.918854 | 1.2 | 3 | 0.216 | office | Edificio de oficinas | {"name":"Bloque hueco de hormigón de árido ligero","source":"ARQ-OF-20260710 · Arquitectura A101 / p. 3, A103 / p. 5, A106 / p. 8; A301Cuadro de materiales ","status":"known"} | {"documented":[{"label":"Espesor del muro","value":0.2,"unit":"m","source":"ARQ-OF-20260710 · Arquitectura A101 / p. 3, A103 / p. 5, A106 / p. 8; A301Cuadro de materiales ","status":"documentado"}],"geometry":[{"label":"Dimensiones de la caja local del elemento (X, Y, Z)","value":"0.9 × 0.2 × 1.2","unit":"m","source":"Malla triangulada del elemento en ejes locales del edificio","status":"derivado"},{"label":"Cota mínima absoluta de la malla","value":287.05,"unit":"m","source":"Malla de proyecto y origen altimétrico 285 m","status":"derivado"},{"label":"Cota máxima absoluta de la malla","value":288.25,"unit":"m","source":"Malla de proyecto y origen altimétrico 285 m","status":"derivado"},{"label":"Volumen geométrico bruto","value":0.216,"unit":"m³","source":"Malla cerrada del elemento","status":"derivado"}],"notes":["Las dimensiones documentadas proceden de anotaciones o cuadros; la caja y el volumen se calculan a partir de la malla.","El volumen es exclusivamente geométrico y bruto; no representa una medición neta de material ni una cantidad de compra."]} | {"documentId":"ARQ-OF-20260710","title":"Planos de arquitectura del edificio de oficinas","date":"2026-07-10","sheet":"Arquitectura A101 / p. 3, A103 / p. 5, A106 / p. 8; A301Cuadro de materiales "} | ["El plano general de 2026-07-31 mantiene el edificio de oficinas de 200 m², mientras documentación anterior indica su supresión. Se conserva lo dibujado, pendiente de confirmación de la propiedad y del equipo de diseño.","Envolvente exterior controlada por la planta de arquitectura; no se han modelado individualmente todas las capas de acabado.","Registro de líneas del PDF general, envolvente de 20 × 10 m; eje local 1 al norte y acceso del lado A al oeste. Estimación de trabajo de implantación de ±0,15 m, pendiente de CAD; no constituye una precisión topográfica garantizada."] | {"horizontalStatus":"derivado","verticalStatus":"derivado","baseElevationM":285.95,"note":"Registro de líneas del PDF general, envolvente de 20 × 10 m; eje local 1 al norte y acceso del lado A al oeste. Estimación de trabajo de implantación de ±0,15 m, pendiente de CAD; no constituye una precisión topográfica garantizada."} | {"Pset_WallCommon":{"IsExternal":{"value":true,"source":"ARQ-OF-20260710 · A101, A103 y alzados; elemento de la envolvente exterior identificada en planta","status":"known"}}} | {"boundingBoxM":{"min":[26.175296,83.72941,2.05],"max":[26.496016,84.648264,3.25]},"extentsM":[0.32072,0.918854,1.2],"meshSurfaceM2":3.0,"meshVolumeM3":0.216,"closedSolid":true,"basis":"Geometría triangulada releída del IFC; envolventes y magnitudes no contractuales."} | {"material":true,"document":true,"quantities":true,"containerGuid":"3ztlotcerHPueDgxP84R6z","containerName":"Planta baja"} | {"id":"architecture","name":"Arquitectura"} | {"profileId":"block_masonry","name":"Fábrica de bloques · acabado mineral claro","materialName":"Bloque hueco de hormigón de árido ligero","physicalMaterialStatus":"known","physicalMaterialSource":"ARQ-OF-20260710 · Arquitectura A101 / p. 3, A103 / p. 5, A106 / p. 8; A301Cuadro de materiales ","appearanceStatus":"criterio_visual","appearanceBasis":"Bloque hueco documentado. Apariencia mineral clara para distinguir el cerramiento; no confirma un revoco ni su espesor.","note":"La apariencia gráfica no modifica ni confirma la especificación física del material."} | {"elementId":"office_0148","ifcGuid":"1P$T$2i$jS8AffcFKG6B5G","ifcClass":"IfcWall","buildingId":"office","buildingName":"Edificio de oficinas","sourceDocumentId":"ARQ-OF-20260710","sourceRepresentationKind":"documentary_mesh"} | {"layerId":"architecture","layerName":"Arquitectura","role":"Muro","basis":"Clasificación por función del elemento; no modifica las especificaciones documentales."} | architecture | {"profileId":"block_masonry","name":"Fábrica de bloques · acabado mineral claro","status":"criterio_visual","basis":"Bloque hueco documentado. Apariencia mineral clara para distinguir el cerramiento; no confirma un revoco ni su espesor.","physicalMaterialUnchanged":true} | ARQ-OF-20260710 · Arquitectura A101 / p. 3, A103 / p. 5, A106 / p. 8; A301Cuadro de materiales | Dimensiones contrastadas con los planos; reconstrucción geométrica a partir de documentación de diseño. | 0.2 | Muros segmentados con huecos reales para puertas y ventanas. | Envolvente exterior controlada por la planta de arquitectura; no se han modelado individualmente todas las capas de acabado. | Registro de líneas del PDF general, envolvente de 20 × 10 m; eje local 1 al norte y acceso del lado A al oeste. Estimación de trabajo de implantación de ±0,15 m, pendiente de CAD; no constituye una precisión topográfica garantizada. | Arquitectura | ARQ-OF-20260710 · Arquitectura A101 / p. 3, A103 / p. 5, A106 / p. 8; A301Cuadro de materiales | 285.95 | Arquitectura | Fábrica de bloques · acabado mineral claro | block_masonry | [0.843137,0.823529,0.772549] | 0.96 | 0 | Bloque hueco documentado. Apariencia mineral clara para distinguir el cerramiento; no confirma un revoco ni su espesor. | Arquitectura; BIM · Arquitectura | El plano general de 2026-07-31 mantiene el edificio de oficinas de 200 m², mientras documentación anterior indica su supresión. Se conserva lo dibujado, pendiente de confirmación de la propiedad y del equipo de diseño.
Edificio de oficinas · Fábrica de bloques huecos de hormigón de 200 mm · eje B · tramo 27 | Planos de arquitectura del edificio de oficinas | Bloque hueco de hormigón de árido ligero | 0.9 × 0.2 × 1.1 | 288.25 | 289.35 | 0.198 | office_0149 | yes | 0.32072 | 0.918854 | 1.1 | 2.78 | 0.198 | office | Edificio de oficinas | {"name":"Bloque hueco de hormigón de árido ligero","source":"ARQ-OF-20260710 · Arquitectura A101 / p. 3, A103 / p. 5, A106 / p. 8; A301Cuadro de materiales ","status":"known"} | {"documented":[{"label":"Espesor del muro","value":0.2,"unit":"m","source":"ARQ-OF-20260710 · Arquitectura A101 / p. 3, A103 / p. 5, A106 / p. 8; A301Cuadro de materiales ","status":"documentado"}],"geometry":[{"label":"Dimensiones de la caja local del elemento (X, Y, Z)","value":"0.9 × 0.2 × 1.1","unit":"m","source":"Malla triangulada del elemento en ejes locales del edificio","status":"derivado"},{"label":"Cota mínima absoluta de la malla","value":288.25,"unit":"m","source":"Malla de proyecto y origen altimétrico 285 m","status":"derivado"},{"label":"Cota máxima absoluta de la malla","value":289.35,"unit":"m","source":"Malla de proyecto y origen altimétrico 285 m","status":"derivado"},{"label":"Volumen geométrico bruto","value":0.198,"unit":"m³","source":"Malla cerrada del elemento","status":"derivado"}],"notes":["Las dimensiones documentadas proceden de anotaciones o cuadros; la caja y el volumen se calculan a partir de la malla.","El volumen es exclusivamente geométrico y bruto; no representa una medición neta de material ni una cantidad de compra."]} | {"documentId":"ARQ-OF-20260710","title":"Planos de arquitectura del edificio de oficinas","date":"2026-07-10","sheet":"Arquitectura A101 / p. 3, A103 / p. 5, A106 / p. 8; A301Cuadro de materiales "} | ["El plano general de 2026-07-31 mantiene el edificio de oficinas de 200 m², mientras documentación anterior indica su supresión. Se conserva lo dibujado, pendiente de confirmación de la propiedad y del equipo de diseño.","Envolvente exterior controlada por la planta de arquitectura; no se han modelado individualmente todas las capas de acabado.","Registro de líneas del PDF general, envolvente de 20 × 10 m; eje local 1 al norte y acceso del lado A al oeste. Estimación de trabajo de implantación de ±0,15 m, pendiente de CAD; no constituye una precisión topográfica garantizada."] | {"horizontalStatus":"derivado","verticalStatus":"derivado","baseElevationM":285.95,"note":"Registro de líneas del PDF general, envolvente de 20 × 10 m; eje local 1 al norte y acceso del lado A al oeste. Estimación de trabajo de implantación de ±0,15 m, pendiente de CAD; no constituye una precisión topográfica garantizada."} | {"Pset_WallCommon":{"IsExternal":{"value":true,"source":"ARQ-OF-20260710 · A101, A103 y alzados; elemento de la envolvente exterior identificada en planta","status":"known"}}} | {"boundingBoxM":{"min":[26.175296,83.72941,3.25],"max":[26.496016,84.648264,4.35]},"extentsM":[0.32072,0.918854,1.1],"meshSurfaceM2":2.78,"meshVolumeM3":0.198,"closedSolid":true,"basis":"Geometría triangulada releída del IFC; envolventes y magnitudes no contractuales."} | {"material":true,"document":true,"quantities":true,"containerGuid":"3ztlotcerHPueDgxP84R6z","containerName":"Planta baja"} | {"id":"architecture","name":"Arquitectura"} | {"profileId":"block_masonry","name":"Fábrica de bloques · acabado mineral claro","materialName":"Bloque hueco de hormigón de árido ligero","physicalMaterialStatus":"known","physicalMaterialSource":"ARQ-OF-20260710 · Arquitectura A101 / p. 3, A103 / p. 5, A106 / p. 8; A301Cuadro de materiales ","appearanceStatus":"criterio_visual","appearanceBasis":"Bloque hueco documentado. Apariencia mineral clara para distinguir el cerramiento; no confirma un revoco ni su espesor.","note":"La apariencia gráfica no modifica ni confirma la especificación física del material."} | {"elementId":"office_0149","ifcGuid":"2JMsuxhWvH2gUrABvNZsmT","ifcClass":"IfcWall","buildingId":"office","buildingName":"Edificio de oficinas","sourceDocumentId":"ARQ-OF-20260710","sourceRepresentationKind":"documentary_mesh"} | {"layerId":"architecture","layerName":"Arquitectura","role":"Muro","basis":"Clasificación por función del elemento; no modifica las especificaciones documentales."} | architecture | {"profileId":"block_masonry","name":"Fábrica de bloques · acabado mineral claro","status":"criterio_visual","basis":"Bloque hueco documentado. Apariencia mineral clara para distinguir el cerramiento; no confirma un revoco ni su espesor.","physicalMaterialUnchanged":true} | ARQ-OF-20260710 · Arquitectura A101 / p. 3, A103 / p. 5, A106 / p. 8; A301Cuadro de materiales | Dimensiones contrastadas con los planos; reconstrucción geométrica a partir de documentación de diseño. | 0.2 | Muros segmentados con huecos reales para puertas y ventanas. | Envolvente exterior controlada por la planta de arquitectura; no se han modelado individualmente todas las capas de acabado. | Registro de líneas del PDF general, envolvente de 20 × 10 m; eje local 1 al norte y acceso del lado A al oeste. Estimación de trabajo de implantación de ±0,15 m, pendiente de CAD; no constituye una precisión topográfica garantizada. | Arquitectura | ARQ-OF-20260710 · Arquitectura A101 / p. 3, A103 / p. 5, A106 / p. 8; A301Cuadro de materiales | 285.95 | Arquitectura | Fábrica de bloques · acabado mineral claro | block_masonry | [0.843137,0.823529,0.772549] | 0.96 | 0 | Bloque hueco documentado. Apariencia mineral clara para distinguir el cerramiento; no confirma un revoco ni su espesor. | Arquitectura; BIM · Arquitectura | El plano general de 2026-07-31 mantiene el edificio de oficinas de 200 m², mientras documentación anterior indica su supresión. Se conserva lo dibujado, pendiente de confirmación de la propiedad y del equipo de diseño.
Edificio de oficinas · Fábrica de bloques huecos de hormigón de 200 mm · eje B · tramo 28 | Planos de arquitectura del edificio de oficinas | Bloque hueco de hormigón de árido ligero | 0.9 × 0.2 × 1.6 | 289.35 | 290.95 | 0.288 | office_0150 | yes | 0.32072 | 0.918854 | 1.6 | 3.88 | 0.288 | office | Edificio de oficinas | {"name":"Bloque hueco de hormigón de árido ligero","source":"ARQ-OF-20260710 · Arquitectura A101 / p. 3, A103 / p. 5, A106 / p. 8; A301Cuadro de materiales ","status":"known"} | {"documented":[{"label":"Espesor del muro","value":0.2,"unit":"m","source":"ARQ-OF-20260710 · Arquitectura A101 / p. 3, A103 / p. 5, A106 / p. 8; A301Cuadro de materiales ","status":"documentado"}],"geometry":[{"label":"Dimensiones de la caja local del elemento (X, Y, Z)","value":"0.9 × 0.2 × 1.6","unit":"m","source":"Malla triangulada del elemento en ejes locales del edificio","status":"derivado"},{"label":"Cota mínima absoluta de la malla","value":289.35,"unit":"m","source":"Malla de proyecto y origen altimétrico 285 m","status":"derivado"},{"label":"Cota máxima absoluta de la malla","value":290.95,"unit":"m","source":"Malla de proyecto y origen altimétrico 285 m","status":"derivado"},{"label":"Volumen geométrico bruto","value":0.288,"unit":"m³","source":"Malla cerrada del elemento","status":"derivado"}],"notes":["Las dimensiones documentadas proceden de anotaciones o cuadros; la caja y el volumen se calculan a partir de la malla.","El volumen es exclusivamente geométrico y bruto; no representa una medición neta de material ni una cantidad de compra."]} | {"documentId":"ARQ-OF-20260710","title":"Planos de arquitectura del edificio de oficinas","date":"2026-07-10","sheet":"Arquitectura A101 / p. 3, A103 / p. 5, A106 / p. 8; A301Cuadro de materiales "} | ["El plano general de 2026-07-31 mantiene el edificio de oficinas de 200 m², mientras documentación anterior indica su supresión. Se conserva lo dibujado, pendiente de confirmación de la propiedad y del equipo de diseño.","Envolvente exterior controlada por la planta de arquitectura; no se han modelado individualmente todas las capas de acabado.","Registro de líneas del PDF general, envolvente de 20 × 10 m; eje local 1 al norte y acceso del lado A al oeste. Estimación de trabajo de implantación de ±0,15 m, pendiente de CAD; no constituye una precisión topográfica garantizada."] | {"horizontalStatus":"derivado","verticalStatus":"derivado","baseElevationM":285.95,"note":"Registro de líneas del PDF general, envolvente de 20 × 10 m; eje local 1 al norte y acceso del lado A al oeste. Estimación de trabajo de implantación de ±0,15 m, pendiente de CAD; no constituye una precisión topográfica garantizada."} | {"Pset_WallCommon":{"IsExternal":{"value":true,"source":"ARQ-OF-20260710 · A101, A103 y alzados; elemento de la envolvente exterior identificada en planta","status":"known"}}} | {"boundingBoxM":{"min":[26.175296,83.72941,4.35],"max":[26.496016,84.648264,5.95]},"extentsM":[0.32072,0.918854,1.6],"meshSurfaceM2":3.88,"meshVolumeM3":0.288,"closedSolid":true,"basis":"Geometría triangulada releída del IFC; envolventes y magnitudes no contractuales."} | {"material":true,"document":true,"quantities":true,"containerGuid":"3ztlotcerHPueDgxP84R6z","containerName":"Planta baja"} | {"id":"architecture","name":"Arquitectura"} | {"profileId":"block_masonry","name":"Fábrica de bloques · acabado mineral claro","materialName":"Bloque hueco de hormigón de árido ligero","physicalMaterialStatus":"known","physicalMaterialSource":"ARQ-OF-20260710 · Arquitectura A101 / p. 3, A103 / p. 5, A106 / p. 8; A301Cuadro de materiales ","appearanceStatus":"criterio_visual","appearanceBasis":"Bloque hueco documentado. Apariencia mineral clara para distinguir el cerramiento; no confirma un revoco ni su espesor.","note":"La apariencia gráfica no modifica ni confirma la especificación física del material."} | {"elementId":"office_0150","ifcGuid":"3$AciiRyXTDBrL2TSD8bdB","ifcClass":"IfcWall","buildingId":"office","buildingName":"Edificio de oficinas","sourceDocumentId":"ARQ-OF-20260710","sourceRepresentationKind":"documentary_mesh"} | {"layerId":"architecture","layerName":"Arquitectura","role":"Muro","basis":"Clasificación por función del elemento; no modifica las especificaciones documentales."} | architecture | {"profileId":"block_masonry","name":"Fábrica de bloques · acabado mineral claro","status":"criterio_visual","basis":"Bloque hueco documentado. Apariencia mineral clara para distinguir el cerramiento; no confirma un revoco ni su espesor.","physicalMaterialUnchanged":true} | ARQ-OF-20260710 · Arquitectura A101 / p. 3, A103 / p. 5, A106 / p. 8; A301Cuadro de materiales | Dimensiones contrastadas con los planos; reconstrucción geométrica a partir de documentación de diseño. | 0.2 | Muros segmentados con huecos reales para puertas y ventanas. | Envolvente exterior controlada por la planta de arquitectura; no se han modelado individualmente todas las capas de acabado. | Registro de líneas del PDF general, envolvente de 20 × 10 m; eje local 1 al norte y acceso del lado A al oeste. Estimación de trabajo de implantación de ±0,15 m, pendiente de CAD; no constituye una precisión topográfica garantizada. | Arquitectura | ARQ-OF-20260710 · Arquitectura A101 / p. 3, A103 / p. 5, A106 / p. 8; A301Cuadro de materiales | 285.95 | Arquitectura | Fábrica de bloques · acabado mineral claro | block_masonry | [0.843137,0.823529,0.772549] | 0.96 | 0 | Bloque hueco documentado. Apariencia mineral clara para distinguir el cerramiento; no confirma un revoco ni su espesor. | Arquitectura; BIM · Arquitectura | El plano general de 2026-07-31 mantiene el edificio de oficinas de 200 m², mientras documentación anterior indica su supresión. Se conserva lo dibujado, pendiente de confirmación de la propiedad y del equipo de diseño.
Edificio de oficinas · Fábrica de bloques huecos de hormigón de 200 mm · eje B · tramo 29 | Planos de arquitectura del edificio de oficinas | Bloque hueco de hormigón de árido ligero | 0.9 × 0.2 × 1.1 | 285.95 | 287.05 | 0.198 | office_0151 | yes | 0.320719 | 0.918854 | 1.1 | 2.78 | 0.198 | office | Edificio de oficinas | {"name":"Bloque hueco de hormigón de árido ligero","source":"ARQ-OF-20260710 · Arquitectura A101 / p. 3, A103 / p. 5, A106 / p. 8; A301Cuadro de materiales ","status":"known"} | {"documented":[{"label":"Espesor del muro","value":0.2,"unit":"m","source":"ARQ-OF-20260710 · Arquitectura A101 / p. 3, A103 / p. 5, A106 / p. 8; A301Cuadro de materiales ","status":"documentado"}],"geometry":[{"label":"Dimensiones de la caja local del elemento (X, Y, Z)","value":"0.9 × 0.2 × 1.1","unit":"m","source":"Malla triangulada del elemento en ejes locales del edificio","status":"derivado"},{"label":"Cota mínima absoluta de la malla","value":285.95,"unit":"m","source":"Malla de proyecto y origen altimétrico 285 m","status":"derivado"},{"label":"Cota máxima absoluta de la malla","value":287.05,"unit":"m","source":"Malla de proyecto y origen altimétrico 285 m","status":"derivado"},{"label":"Volumen geométrico bruto","value":0.198,"unit":"m³","source":"Malla cerrada del elemento","status":"derivado"}],"notes":["Las dimensiones documentadas proceden de anotaciones o cuadros; la caja y el volumen se calculan a partir de la malla.","El volumen es exclusivamente geométrico y bruto; no representa una medición neta de material ni una cantidad de compra."]} | {"documentId":"ARQ-OF-20260710","title":"Planos de arquitectura del edificio de oficinas","date":"2026-07-10","sheet":"Arquitectura A101 / p. 3, A103 / p. 5, A106 / p. 8; A301Cuadro de materiales "} | ["El plano general de 2026-07-31 mantiene el edificio de oficinas de 200 m², mientras documentación anterior indica su supresión. Se conserva lo dibujado, pendiente de confirmación de la propiedad y del equipo de diseño.","Envolvente exterior controlada por la planta de arquitectura; no se han modelado individualmente todas las capas de acabado.","Registro de líneas del PDF general, envolvente de 20 × 10 m; eje local 1 al norte y acceso del lado A al oeste. Estimación de trabajo de implantación de ±0,15 m, pendiente de CAD; no constituye una precisión topográfica garantizada."] | {"horizontalStatus":"derivado","verticalStatus":"derivado","baseElevationM":285.95,"note":"Registro de líneas del PDF general, envolvente de 20 × 10 m; eje local 1 al norte y acceso del lado A al oeste. Estimación de trabajo de implantación de ±0,15 m, pendiente de CAD; no constituye una precisión topográfica garantizada."} | {"Pset_WallCommon":{"IsExternal":{"value":true,"source":"ARQ-OF-20260710 · A101, A103 y alzados; elemento de la envolvente exterior identificada en planta","status":"known"}}} | {"boundingBoxM":{"min":[26.052713,82.837797,0.95],"max":[26.373432,83.756651,2.05]},"extentsM":[0.320719,0.918854,1.1],"meshSurfaceM2":2.78,"meshVolumeM3":0.198,"closedSolid":true,"basis":"Geometría triangulada releída del IFC; envolventes y magnitudes no contractuales."} | {"material":true,"document":true,"quantities":true,"containerGuid":"3ztlotcerHPueDgxP84R6z","containerName":"Planta baja"} | {"id":"architecture","name":"Arquitectura"} | {"profileId":"block_masonry","name":"Fábrica de bloques · acabado mineral claro","materialName":"Bloque hueco de hormigón de árido ligero","physicalMaterialStatus":"known","physicalMaterialSource":"ARQ-OF-20260710 · Arquitectura A101 / p. 3, A103 / p. 5, A106 / p. 8; A301Cuadro de materiales ","appearanceStatus":"criterio_visual","appearanceBasis":"Bloque hueco documentado. Apariencia mineral clara para distinguir el cerramiento; no confirma un revoco ni su espesor.","note":"La apariencia gráfica no modifica ni confirma la especificación física del material."} | {"elementId":"office_0151","ifcGuid":"27dWFQf75J7OLL8GWEbPZa","ifcClass":"IfcWall","buildingId":"office","buildingName":"Edificio de oficinas","sourceDocumentId":"ARQ-OF-20260710","sourceRepresentationKind":"documentary_mesh"} | {"layerId":"architecture","layerName":"Arquitectura","role":"Muro","basis":"Clasificación por función del elemento; no modifica las especificaciones documentales."} | architecture | {"profileId":"block_masonry","name":"Fábrica de bloques · acabado mineral claro","status":"criterio_visual","basis":"Bloque hueco documentado. Apariencia mineral clara para distinguir el cerramiento; no confirma un revoco ni su espesor.","physicalMaterialUnchanged":true} | ARQ-OF-20260710 · Arquitectura A101 / p. 3, A103 / p. 5, A106 / p. 8; A301Cuadro de materiales | Dimensiones contrastadas con los planos; reconstrucción geométrica a partir de documentación de diseño. | 0.2 | Muros segmentados con huecos reales para puertas y ventanas. | Envolvente exterior controlada por la planta de arquitectura; no se han modelado individualmente todas las capas de acabado. | Registro de líneas del PDF general, envolvente de 20 × 10 m; eje local 1 al norte y acceso del lado A al oeste. Estimación de trabajo de implantación de ±0,15 m, pendiente de CAD; no constituye una precisión topográfica garantizada. | Arquitectura | ARQ-OF-20260710 · Arquitectura A101 / p. 3, A103 / p. 5, A106 / p. 8; A301Cuadro de materiales | 285.95 | Arquitectura | Fábrica de bloques · acabado mineral claro | block_masonry | [0.843137,0.823529,0.772549] | 0.96 | 0 | Bloque hueco documentado. Apariencia mineral clara para distinguir el cerramiento; no confirma un revoco ni su espesor. | Arquitectura; BIM · Arquitectura | El plano general de 2026-07-31 mantiene el edificio de oficinas de 200 m², mientras documentación anterior indica su supresión. Se conserva lo dibujado, pendiente de confirmación de la propiedad y del equipo de diseño.
Edificio de oficinas · Fábrica de bloques huecos de hormigón de 200 mm · eje B · tramo 30 | Planos de arquitectura del edificio de oficinas | Bloque hueco de hormigón de árido ligero | 0.9 × 0.2 × 1.6 | 289.35 | 290.95 | 0.288 | office_0152 | yes | 0.320719 | 0.918854 | 1.6 | 3.88 | 0.288 | office | Edificio de oficinas | {"name":"Bloque hueco de hormigón de árido ligero","source":"ARQ-OF-20260710 · Arquitectura A101 / p. 3, A103 / p. 5, A106 / p. 8; A301Cuadro de materiales ","status":"known"} | {"documented":[{"label":"Espesor del muro","value":0.2,"unit":"m","source":"ARQ-OF-20260710 · Arquitectura A101 / p. 3, A103 / p. 5, A106 / p. 8; A301Cuadro de materiales ","status":"documentado"}],"geometry":[{"label":"Dimensiones de la caja local del elemento (X, Y, Z)","value":"0.9 × 0.2 × 1.6","unit":"m","source":"Malla triangulada del elemento en ejes locales del edificio","status":"derivado"},{"label":"Cota mínima absoluta de la malla","value":289.35,"unit":"m","source":"Malla de proyecto y origen altimétrico 285 m","status":"derivado"},{"label":"Cota máxima absoluta de la malla","value":290.95,"unit":"m","source":"Malla de proyecto y origen altimétrico 285 m","status":"derivado"},{"label":"Volumen geométrico bruto","value":0.288,"unit":"m³","source":"Malla cerrada del elemento","status":"derivado"}],"notes":["Las dimensiones documentadas proceden de anotaciones o cuadros; la caja y el volumen se calculan a partir de la malla.","El volumen es exclusivamente geométrico y bruto; no representa una medición neta de material ni una cantidad de compra."]} | {"documentId":"ARQ-OF-20260710","title":"Planos de arquitectura del edificio de oficinas","date":"2026-07-10","sheet":"Arquitectura A101 / p. 3, A103 / p. 5, A106 / p. 8; A301Cuadro de materiales "} | ["El plano general de 2026-07-31 mantiene el edificio de oficinas de 200 m², mientras documentación anterior indica su supresión. Se conserva lo dibujado, pendiente de confirmación de la propiedad y del equipo de diseño.","Envolvente exterior controlada por la planta de arquitectura; no se han modelado individualmente todas las capas de acabado.","Registro de líneas del PDF general, envolvente de 20 × 10 m; eje local 1 al norte y acceso del lado A al oeste. Estimación de trabajo de implantación de ±0,15 m, pendiente de CAD; no constituye una precisión topográfica garantizada."] | {"horizontalStatus":"derivado","verticalStatus":"derivado","baseElevationM":285.95,"note":"Registro de líneas del PDF general, envolvente de 20 × 10 m; eje local 1 al norte y acceso del lado A al oeste. Estimación de trabajo de implantación de ±0,15 m, pendiente de CAD; no constituye una precisión topográfica garantizada."} | {"Pset_WallCommon":{"IsExternal":{"value":true,"source":"ARQ-OF-20260710 · A101, A103 y alzados; elemento de la envolvente exterior identificada en planta","status":"known"}}} | {"boundingBoxM":{"min":[26.052713,82.837797,4.35],"max":[26.373432,83.756651,5.95]},"extentsM":[0.320719,0.918854,1.6],"meshSurfaceM2":3.88,"meshVolumeM3":0.288,"closedSolid":true,"basis":"Geometría triangulada releída del IFC; envolventes y magnitudes no contractuales."} | {"material":true,"document":true,"quantities":true,"containerGuid":"3ztlotcerHPueDgxP84R6z","containerName":"Planta baja"} | {"id":"architecture","name":"Arquitectura"} | {"profileId":"block_masonry","name":"Fábrica de bloques · acabado mineral claro","materialName":"Bloque hueco de hormigón de árido ligero","physicalMaterialStatus":"known","physicalMaterialSource":"ARQ-OF-20260710 · Arquitectura A101 / p. 3, A103 / p. 5, A106 / p. 8; A301Cuadro de materiales ","appearanceStatus":"criterio_visual","appearanceBasis":"Bloque hueco documentado. Apariencia mineral clara para distinguir el cerramiento; no confirma un revoco ni su espesor.","note":"La apariencia gráfica no modifica ni confirma la especificación física del material."} | {"elementId":"office_0152","ifcGuid":"1AhyVI4Y1RE8wKGPOUcZBY","ifcClass":"IfcWall","buildingId":"office","buildingName":"Edificio de oficinas","sourceDocumentId":"ARQ-OF-20260710","sourceRepresentationKind":"documentary_mesh"} | {"layerId":"architecture","layerName":"Arquitectura","role":"Muro","basis":"Clasificación por función del elemento; no modifica las especificaciones documentales."} | architecture | {"profileId":"block_masonry","name":"Fábrica de bloques · acabado mineral claro","status":"criterio_visual","basis":"Bloque hueco documentado. Apariencia mineral clara para distinguir el cerramiento; no confirma un revoco ni su espesor.","physicalMaterialUnchanged":true} | ARQ-OF-20260710 · Arquitectura A101 / p. 3, A103 / p. 5, A106 / p. 8; A301Cuadro de materiales | Dimensiones contrastadas con los planos; reconstrucción geométrica a partir de documentación de diseño. | 0.2 | Muros segmentados con huecos reales para puertas y ventanas. | Envolvente exterior controlada por la planta de arquitectura; no se han modelado individualmente todas las capas de acabado. | Registro de líneas del PDF general, envolvente de 20 × 10 m; eje local 1 al norte y acceso del lado A al oeste. Estimación de trabajo de implantación de ±0,15 m, pendiente de CAD; no constituye una precisión topográfica garantizada. | Arquitectura | ARQ-OF-20260710 · Arquitectura A101 / p. 3, A103 / p. 5, A106 / p. 8; A301Cuadro de materiales | 285.95 | Arquitectura | Fábrica de bloques · acabado mineral claro | block_masonry | [0.843137,0.823529,0.772549] | 0.96 | 0 | Bloque hueco documentado. Apariencia mineral clara para distinguir el cerramiento; no confirma un revoco ni su espesor. | Arquitectura; BIM · Arquitectura | El plano general de 2026-07-31 mantiene el edificio de oficinas de 200 m², mientras documentación anterior indica su supresión. Se conserva lo dibujado, pendiente de confirmación de la propiedad y del equipo de diseño.
Edificio de oficinas · Fábrica de bloques huecos de hormigón de 200 mm · eje B · tramo 31 | Planos de arquitectura del edificio de oficinas | Bloque hueco de hormigón de árido ligero | 1.5 × 0.2 × 1.1 | 285.95 | 287.05 | 0.33 | office_0153 | yes | 0.402442 | 1.51326 | 1.1 | 4.34 | 0.33 | office | Edificio de oficinas | {"name":"Bloque hueco de hormigón de árido ligero","source":"ARQ-OF-20260710 · Arquitectura A101 / p. 3, A103 / p. 5, A106 / p. 8; A301Cuadro de materiales ","status":"known"} | {"documented":[{"label":"Espesor del muro","value":0.2,"unit":"m","source":"ARQ-OF-20260710 · Arquitectura A101 / p. 3, A103 / p. 5, A106 / p. 8; A301Cuadro de materiales ","status":"documentado"}],"geometry":[{"label":"Dimensiones de la caja local del elemento (X, Y, Z)","value":"1.5 × 0.2 × 1.1","unit":"m","source":"Malla triangulada del elemento en ejes locales del edificio","status":"derivado"},{"label":"Cota mínima absoluta de la malla","value":285.95,"unit":"m","source":"Malla de proyecto y origen altimétrico 285 m","status":"derivado"},{"label":"Cota máxima absoluta de la malla","value":287.05,"unit":"m","source":"Malla de proyecto y origen altimétrico 285 m","status":"derivado"},{"label":"Volumen geométrico bruto","value":0.33,"unit":"m³","source":"Malla cerrada del elemento","status":"derivado"}],"notes":["Las dimensiones documentadas proceden de anotaciones o cuadros; la caja y el volumen se calculan a partir de la malla.","El volumen es exclusivamente geométrico y bruto; no representa una medición neta de material ni una cantidad de compra."]} | {"documentId":"ARQ-OF-20260710","title":"Planos de arquitectura del edificio de oficinas","date":"2026-07-10","sheet":"Arquitectura A101 / p. 3, A103 / p. 5, A106 / p. 8; A301Cuadro de materiales "} | ["El plano general de 2026-07-31 mantiene el edificio de oficinas de 200 m², mientras documentación anterior indica su supresión. Se conserva lo dibujado, pendiente de confirmación de la propiedad y del equipo de diseño.","Envolvente exterior controlada por la planta de arquitectura; no se han modelado individualmente todas las capas de acabado.","Registro de líneas del PDF general, envolvente de 20 × 10 m; eje local 1 al norte y acceso del lado A al oeste. Estimación de trabajo de implantación de ±0,15 m, pendiente de CAD; no constituye una precisión topográfica garantizada."] | {"horizontalStatus":"derivado","verticalStatus":"derivado","baseElevationM":285.95,"note":"Registro de líneas del PDF general, envolvente de 20 × 10 m; eje local 1 al norte y acceso del lado A al oeste. Estimación de trabajo de implantación de ±0,15 m, pendiente de CAD; no constituye una precisión topográfica garantizada."} | {"Pset_WallCommon":{"IsExternal":{"value":true,"source":"ARQ-OF-20260710 · A101, A103 y alzados; elemento de la envolvente exterior identificada en planta","status":"known"}}} | {"boundingBoxM":{"min":[25.848407,81.351776,0.95],"max":[26.250849,82.865038,2.05]},"extentsM":[0.402442,1.513262,1.1],"meshSurfaceM2":4.339999,"meshVolumeM3":0.33,"closedSolid":true,"basis":"Geometría triangulada releída del IFC; envolventes y magnitudes no contractuales."} | {"material":true,"document":true,"quantities":true,"containerGuid":"3ztlotcerHPueDgxP84R6z","containerName":"Planta baja"} | {"id":"architecture","name":"Arquitectura"} | {"profileId":"block_masonry","name":"Fábrica de bloques · acabado mineral claro","materialName":"Bloque hueco de hormigón de árido ligero","physicalMaterialStatus":"known","physicalMaterialSource":"ARQ-OF-20260710 · Arquitectura A101 / p. 3, A103 / p. 5, A106 / p. 8; A301Cuadro de materiales ","appearanceStatus":"criterio_visual","appearanceBasis":"Bloque hueco documentado. Apariencia mineral clara para distinguir el cerramiento; no confirma un revoco ni su espesor.","note":"La apariencia gráfica no modifica ni confirma la especificación física del material."} | {"elementId":"office_0153","ifcGuid":"0EGM97rC1KqAW0daYvCpT0","ifcClass":"IfcWall","buildingId":"office","buildingName":"Edificio de oficinas","sourceDocumentId":"ARQ-OF-20260710","sourceRepresentationKind":"documentary_mesh"} | {"layerId":"architecture","layerName":"Arquitectura","role":"Muro","basis":"Clasificación por función del elemento; no modifica las especificaciones documentales."} | architecture | {"profileId":"block_masonry","name":"Fábrica de bloques · acabado mineral claro","status":"criterio_visual","basis":"Bloque hueco documentado. Apariencia mineral clara para distinguir el cerramiento; no confirma un revoco ni su espesor.","physicalMaterialUnchanged":true} | ARQ-OF-20260710 · Arquitectura A101 / p. 3, A103 / p. 5, A106 / p. 8; A301Cuadro de materiales | Dimensiones contrastadas con los planos; reconstrucción geométrica a partir de documentación de diseño. | 0.2 | Muros segmentados con huecos reales para puertas y ventanas. | Envolvente exterior controlada por la planta de arquitectura; no se han modelado individualmente todas las capas de acabado. | Registro de líneas del PDF general, envolvente de 20 × 10 m; eje local 1 al norte y acceso del lado A al oeste. Estimación de trabajo de implantación de ±0,15 m, pendiente de CAD; no constituye una precisión topográfica garantizada. | Arquitectura | ARQ-OF-20260710 · Arquitectura A101 / p. 3, A103 / p. 5, A106 / p. 8; A301Cuadro de materiales | 285.95 | Arquitectura | Fábrica de bloques · acabado mineral claro | block_masonry | [0.843137,0.823529,0.772549] | 0.96 | 0 | Bloque hueco documentado. Apariencia mineral clara para distinguir el cerramiento; no confirma un revoco ni su espesor. | Arquitectura; BIM · Arquitectura | El plano general de 2026-07-31 mantiene el edificio de oficinas de 200 m², mientras documentación anterior indica su supresión. Se conserva lo dibujado, pendiente de confirmación de la propiedad y del equipo de diseño.
Edificio de oficinas · Fábrica de bloques huecos de hormigón de 200 mm · eje B · tramo 32 | Planos de arquitectura del edificio de oficinas | Bloque hueco de hormigón de árido ligero | 1.5 × 0.2 × 1.2 | 287.05 | 288.25 | 0.36 | office_0154 | yes | 0.402442 | 1.51326 | 1.2 | 4.68 | 0.36 | office | Edificio de oficinas | {"name":"Bloque hueco de hormigón de árido ligero","source":"ARQ-OF-20260710 · Arquitectura A101 / p. 3, A103 / p. 5, A106 / p. 8; A301Cuadro de materiales ","status":"known"} | {"documented":[{"label":"Espesor del muro","value":0.2,"unit":"m","source":"ARQ-OF-20260710 · Arquitectura A101 / p. 3, A103 / p. 5, A106 / p. 8; A301Cuadro de materiales ","status":"documentado"}],"geometry":[{"label":"Dimensiones de la caja local del elemento (X, Y, Z)","value":"1.5 × 0.2 × 1.2","unit":"m","source":"Malla triangulada del elemento en ejes locales del edificio","status":"derivado"},{"label":"Cota mínima absoluta de la malla","value":287.05,"unit":"m","source":"Malla de proyecto y origen altimétrico 285 m","status":"derivado"},{"label":"Cota máxima absoluta de la malla","value":288.25,"unit":"m","source":"Malla de proyecto y origen altimétrico 285 m","status":"derivado"},{"label":"Volumen geométrico bruto","value":0.36,"unit":"m³","source":"Malla cerrada del elemento","status":"derivado"}],"notes":["Las dimensiones documentadas proceden de anotaciones o cuadros; la caja y el volumen se calculan a partir de la malla.","El volumen es exclusivamente geométrico y bruto; no representa una medición neta de material ni una cantidad de compra."]} | {"documentId":"ARQ-OF-20260710","title":"Planos de arquitectura del edificio de oficinas","date":"2026-07-10","sheet":"Arquitectura A101 / p. 3, A103 / p. 5, A106 / p. 8; A301Cuadro de materiales "} | ["El plano general de 2026-07-31 mantiene el edificio de oficinas de 200 m², mientras documentación anterior indica su supresión. Se conserva lo dibujado, pendiente de confirmación de la propiedad y del equipo de diseño.","Envolvente exterior controlada por la planta de arquitectura; no se han modelado individualmente todas las capas de acabado.","Registro de líneas del PDF general, envolvente de 20 × 10 m; eje local 1 al norte y acceso del lado A al oeste. Estimación de trabajo de implantación de ±0,15 m, pendiente de CAD; no constituye una precisión topográfica garantizada."] | {"horizontalStatus":"derivado","verticalStatus":"derivado","baseElevationM":285.95,"note":"Registro de líneas del PDF general, envolvente de 20 × 10 m; eje local 1 al norte y acceso del lado A al oeste. Estimación de trabajo de implantación de ±0,15 m, pendiente de CAD; no constituye una precisión topográfica garantizada."} | {"Pset_WallCommon":{"IsExternal":{"value":true,"source":"ARQ-OF-20260710 · A101, A103 y alzados; elemento de la envolvente exterior identificada en planta","status":"known"}}} | {"boundingBoxM":{"min":[25.848407,81.351776,2.05],"max":[26.250849,82.865038,3.25]},"extentsM":[0.402442,1.513262,1.2],"meshSurfaceM2":4.679999,"meshVolumeM3":0.36,"closedSolid":true,"basis":"Geometría triangulada releída del IFC; envolventes y magnitudes no contractuales."} | {"material":true,"document":true,"quantities":true,"containerGuid":"3ztlotcerHPueDgxP84R6z","containerName":"Planta baja"} | {"id":"architecture","name":"Arquitectura"} | {"profileId":"block_masonry","name":"Fábrica de bloques · acabado mineral claro","materialName":"Bloque hueco de hormigón de árido ligero","physicalMaterialStatus":"known","physicalMaterialSource":"ARQ-OF-20260710 · Arquitectura A101 / p. 3, A103 / p. 5, A106 / p. 8; A301Cuadro de materiales ","appearanceStatus":"criterio_visual","appearanceBasis":"Bloque hueco documentado. Apariencia mineral clara para distinguir el cerramiento; no confirma un revoco ni su espesor.","note":"La apariencia gráfica no modifica ni confirma la especificación física del material."} | {"elementId":"office_0154","ifcGuid":"3Ep5jtbt5U4goWRP1GA52g","ifcClass":"IfcWall","buildingId":"office","buildingName":"Edificio de oficinas","sourceDocumentId":"ARQ-OF-20260710","sourceRepresentationKind":"documentary_mesh"} | {"layerId":"architecture","layerName":"Arquitectura","role":"Muro","basis":"Clasificación por función del elemento; no modifica las especificaciones documentales."} | architecture | {"profileId":"block_masonry","name":"Fábrica de bloques · acabado mineral claro","status":"criterio_visual","basis":"Bloque hueco documentado. Apariencia mineral clara para distinguir el cerramiento; no confirma un revoco ni su espesor.","physicalMaterialUnchanged":true} | ARQ-OF-20260710 · Arquitectura A101 / p. 3, A103 / p. 5, A106 / p. 8; A301Cuadro de materiales | Dimensiones contrastadas con los planos; reconstrucción geométrica a partir de documentación de diseño. | 0.2 | Muros segmentados con huecos reales para puertas y ventanas. | Envolvente exterior controlada por la planta de arquitectura; no se han modelado individualmente todas las capas de acabado. | Registro de líneas del PDF general, envolvente de 20 × 10 m; eje local 1 al norte y acceso del lado A al oeste. Estimación de trabajo de implantación de ±0,15 m, pendiente de CAD; no constituye una precisión topográfica garantizada. | Arquitectura | ARQ-OF-20260710 · Arquitectura A101 / p. 3, A103 / p. 5, A106 / p. 8; A301Cuadro de materiales | 285.95 | Arquitectura | Fábrica de bloques · acabado mineral claro | block_masonry | [0.843137,0.823529,0.772549] | 0.96 | 0 | Bloque hueco documentado. Apariencia mineral clara para distinguir el cerramiento; no confirma un revoco ni su espesor. | Arquitectura; BIM · Arquitectura | El plano general de 2026-07-31 mantiene el edificio de oficinas de 200 m², mientras documentación anterior indica su supresión. Se conserva lo dibujado, pendiente de confirmación de la propiedad y del equipo de diseño.
Edificio de oficinas · Fábrica de bloques huecos de hormigón de 200 mm · eje B · tramo 33 | Planos de arquitectura del edificio de oficinas | Bloque hueco de hormigón de árido ligero | 1.5 × 0.2 × 1.1 | 288.25 | 289.35 | 0.33 | office_0155 | yes | 0.402442 | 1.51326 | 1.1 | 4.34 | 0.33 | office | Edificio de oficinas | {"name":"Bloque hueco de hormigón de árido ligero","source":"ARQ-OF-20260710 · Arquitectura A101 / p. 3, A103 / p. 5, A106 / p. 8; A301Cuadro de materiales ","status":"known"} | {"documented":[{"label":"Espesor del muro","value":0.2,"unit":"m","source":"ARQ-OF-20260710 · Arquitectura A101 / p. 3, A103 / p. 5, A106 / p. 8; A301Cuadro de materiales ","status":"documentado"}],"geometry":[{"label":"Dimensiones de la caja local del elemento (X, Y, Z)","value":"1.5 × 0.2 × 1.1","unit":"m","source":"Malla triangulada del elemento en ejes locales del edificio","status":"derivado"},{"label":"Cota mínima absoluta de la malla","value":288.25,"unit":"m","source":"Malla de proyecto y origen altimétrico 285 m","status":"derivado"},{"label":"Cota máxima absoluta de la malla","value":289.35,"unit":"m","source":"Malla de proyecto y origen altimétrico 285 m","status":"derivado"},{"label":"Volumen geométrico bruto","value":0.33,"unit":"m³","source":"Malla cerrada del elemento","status":"derivado"}],"notes":["Las dimensiones documentadas proceden de anotaciones o cuadros; la caja y el volumen se calculan a partir de la malla.","El volumen es exclusivamente geométrico y bruto; no representa una medición neta de material ni una cantidad de compra."]} | {"documentId":"ARQ-OF-20260710","title":"Planos de arquitectura del edificio de oficinas","date":"2026-07-10","sheet":"Arquitectura A101 / p. 3, A103 / p. 5, A106 / p. 8; A301Cuadro de materiales "} | ["El plano general de 2026-07-31 mantiene el edificio de oficinas de 200 m², mientras documentación anterior indica su supresión. Se conserva lo dibujado, pendiente de confirmación de la propiedad y del equipo de diseño.","Envolvente exterior controlada por la planta de arquitectura; no se han modelado individualmente todas las capas de acabado.","Registro de líneas del PDF general, envolvente de 20 × 10 m; eje local 1 al norte y acceso del lado A al oeste. Estimación de trabajo de implantación de ±0,15 m, pendiente de CAD; no constituye una precisión topográfica garantizada."] | {"horizontalStatus":"derivado","verticalStatus":"derivado","baseElevationM":285.95,"note":"Registro de líneas del PDF general, envolvente de 20 × 10 m; eje local 1 al norte y acceso del lado A al oeste. Estimación de trabajo de implantación de ±0,15 m, pendiente de CAD; no constituye una precisión topográfica garantizada."} | {"Pset_WallCommon":{"IsExternal":{"value":true,"source":"ARQ-OF-20260710 · A101, A103 y alzados; elemento de la envolvente exterior identificada en planta","status":"known"}}} | {"boundingBoxM":{"min":[25.848407,81.351776,3.25],"max":[26.250849,82.865038,4.35]},"extentsM":[0.402442,1.513262,1.1],"meshSurfaceM2":4.339999,"meshVolumeM3":0.33,"closedSolid":true,"basis":"Geometría triangulada releída del IFC; envolventes y magnitudes no contractuales."} | {"material":true,"document":true,"quantities":true,"containerGuid":"3ztlotcerHPueDgxP84R6z","containerName":"Planta baja"} | {"id":"architecture","name":"Arquitectura"} | {"profileId":"block_masonry","name":"Fábrica de bloques · acabado mineral claro","materialName":"Bloque hueco de hormigón de árido ligero","physicalMaterialStatus":"known","physicalMaterialSource":"ARQ-OF-20260710 · Arquitectura A101 / p. 3, A103 / p. 5, A106 / p. 8; A301Cuadro de materiales ","appearanceStatus":"criterio_visual","appearanceBasis":"Bloque hueco documentado. Apariencia mineral clara para distinguir el cerramiento; no confirma un revoco ni su espesor.","note":"La apariencia gráfica no modifica ni confirma la especificación física del material."} | {"elementId":"office_0155","ifcGuid":"3$fvZsOaTV6uFZe3ROblLY","ifcClass":"IfcWall","buildingId":"office","buildingName":"Edificio de oficinas","sourceDocumentId":"ARQ-OF-20260710","sourceRepresentationKind":"documentary_mesh"} | {"layerId":"architecture","layerName":"Arquitectura","role":"Muro","basis":"Clasificación por función del elemento; no modifica las especificaciones documentales."} | architecture | {"profileId":"block_masonry","name":"Fábrica de bloques · acabado mineral claro","status":"criterio_visual","basis":"Bloque hueco documentado. Apariencia mineral clara para distinguir el cerramiento; no confirma un revoco ni su espesor.","physicalMaterialUnchanged":true} | ARQ-OF-20260710 · Arquitectura A101 / p. 3, A103 / p. 5, A106 / p. 8; A301Cuadro de materiales | Dimensiones contrastadas con los planos; reconstrucción geométrica a partir de documentación de diseño. | 0.2 | Muros segmentados con huecos reales para puertas y ventanas. | Envolvente exterior controlada por la planta de arquitectura; no se han modelado individualmente todas las capas de acabado. | Registro de líneas del PDF general, envolvente de 20 × 10 m; eje local 1 al norte y acceso del lado A al oeste. Estimación de trabajo de implantación de ±0,15 m, pendiente de CAD; no constituye una precisión topográfica garantizada. | Arquitectura | ARQ-OF-20260710 · Arquitectura A101 / p. 3, A103 / p. 5, A106 / p. 8; A301Cuadro de materiales | 285.95 | Arquitectura | Fábrica de bloques · acabado mineral claro | block_masonry | [0.843137,0.823529,0.772549] | 0.96 | 0 | Bloque hueco documentado. Apariencia mineral clara para distinguir el cerramiento; no confirma un revoco ni su espesor. | Arquitectura; BIM · Arquitectura | El plano general de 2026-07-31 mantiene el edificio de oficinas de 200 m², mientras documentación anterior indica su supresión. Se conserva lo dibujado, pendiente de confirmación de la propiedad y del equipo de diseño.
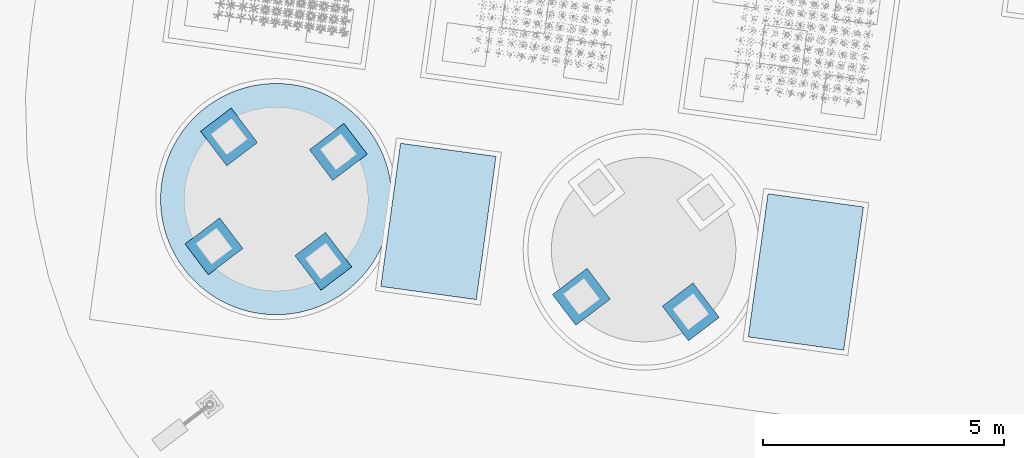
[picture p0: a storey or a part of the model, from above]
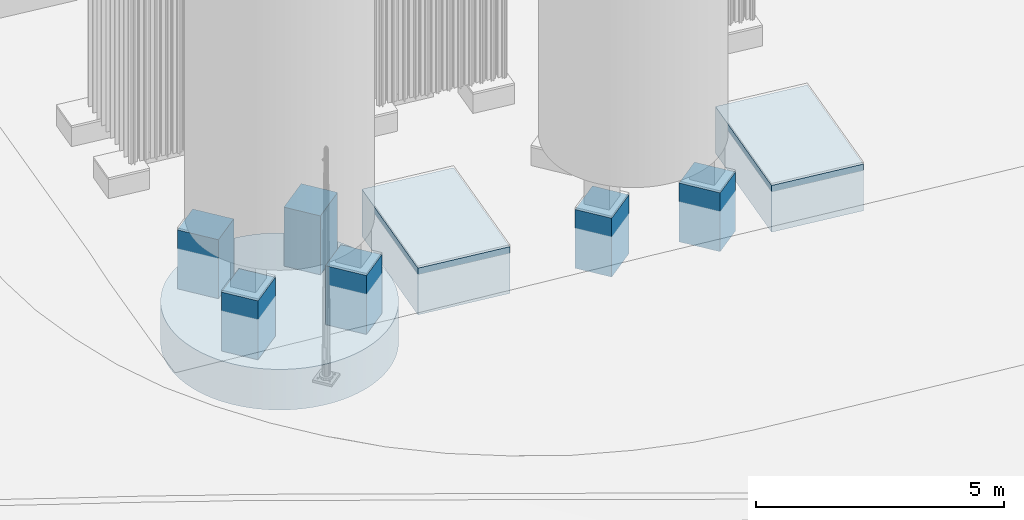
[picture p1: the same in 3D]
Properties of the parts of a building model (IFC4), part 126 of 134

# IfcWall (187)
Name | Document | Material = JH_Trazabilidad, Material = name | Dimensiones de la caja local del elemento (X, Y, Z) | Cota mínima absoluta de la malla (m) | Cota máxima absoluta de la malla (m) | Volumen geométrico bruto (m3) = Volumen geométrico (m³) | Reference = Identificador del elemento = Identificador | IsExternal | ExtensionX (m) | ExtensionY (m) | ExtensionZ (m) | SuperficieDeLaMalla (m2) | VolumenGeometrico (m3) = GrossVolume (m3) | buildingId | buildingName = Edificio | material | dimensions | JH_InformacionBIM, source = DocumentoFuente | issues = IncidenciasPendientes | positioning = PosicionYEstado | commonProperties | geometryMetrics | ifcAssociations | visualLayer | materialAppearance | visualizationIdentity | classification | layerId = IdentificadorCapa | appearance | Planos de referencia | Base geométrica | Espesor del muro (m) = Espesor del muro (m) | Tratamiento de los huecos | Representación de los acabados | Estado de la implantación | Disciplina | Referencia del material = JH_EvidenciaDeMaterial, source | Cota de planta baja terminada (m) | Capa BIM = NombreCapa | Acabado de visualización = Acabado | Perfil | ColorRGB | Rugosidad | Metallicidad | Referencia | Group | Discrepancia entre versiones
Edificio de oficinas · Fábrica de bloques huecos de hormigón de 200 mm · eje B · tramo 34 | Planos de arquitectura del edificio de oficinas | Bloque hueco de hormigón de árido ligero | 1.5 × 0.2 × 1.6 | 289.35 | 290.95 | 0.48 | office_0156 | yes | 0.402442 | 1.51326 | 1.6 | 6.04 | 0.48 | office | Edificio de oficinas | {"name":"Bloque hueco de hormigón de árido ligero","source":"ARQ-OF-20260710 · Arquitectura A101 / p. 3, A103 / p. 5, A106 / p. 8; A301Cuadro de materiales ","status":"known"} | {"documented":[{"label":"Espesor del muro","value":0.2,"unit":"m","source":"ARQ-OF-20260710 · Arquitectura A101 / p. 3, A103 / p. 5, A106 / p. 8; A301Cuadro de materiales ","status":"documentado"}],"geometry":[{"label":"Dimensiones de la caja local del elemento (X, Y, Z)","value":"1.5 × 0.2 × 1.6","unit":"m","source":"Malla triangulada del elemento en ejes locales del edificio","status":"derivado"},{"label":"Cota mínima absoluta de la malla","value":289.35,"unit":"m","source":"Malla de proyecto y origen altimétrico 285 m","status":"derivado"},{"label":"Cota máxima absoluta de la malla","value":290.95,"unit":"m","source":"Malla de proyecto y origen altimétrico 285 m","status":"derivado"},{"label":"Volumen geométrico bruto","value":0.48,"unit":"m³","source":"Malla cerrada del elemento","status":"derivado"}],"notes":["Las dimensiones documentadas proceden de anotaciones o cuadros; la caja y el volumen se calculan a partir de la malla.","El volumen es exclusivamente geométrico y bruto; no representa una medición neta de material ni una cantidad de compra."]} | {"documentId":"ARQ-OF-20260710","title":"Planos de arquitectura del edificio de oficinas","date":"2026-07-10","sheet":"Arquitectura A101 / p. 3, A103 / p. 5, A106 / p. 8; A301Cuadro de materiales "} | ["El plano general de 2026-07-31 mantiene el edificio de oficinas de 200 m², mientras documentación anterior indica su supresión. Se conserva lo dibujado, pendiente de confirmación de la propiedad y del equipo de diseño.","Envolvente exterior controlada por la planta de arquitectura; no se han modelado individualmente todas las capas de acabado.","Registro de líneas del PDF general, envolvente de 20 × 10 m; eje local 1 al norte y acceso del lado A al oeste. Estimación de trabajo de implantación de ±0,15 m, pendiente de CAD; no constituye una precisión topográfica garantizada."] | {"horizontalStatus":"derivado","verticalStatus":"derivado","baseElevationM":285.95,"note":"Registro de líneas del PDF general, envolvente de 20 × 10 m; eje local 1 al norte y acceso del lado A al oeste. Estimación de trabajo de implantación de ±0,15 m, pendiente de CAD; no constituye una precisión topográfica garantizada."} | {"Pset_WallCommon":{"IsExternal":{"value":true,"source":"ARQ-OF-20260710 · A101, A103 y alzados; elemento de la envolvente exterior identificada en planta","status":"known"}}} | {"boundingBoxM":{"min":[25.848407,81.351776,4.35],"max":[26.250849,82.865038,5.95]},"extentsM":[0.402442,1.513262,1.6],"meshSurfaceM2":6.039998,"meshVolumeM3":0.48,"closedSolid":true,"basis":"Geometría triangulada releída del IFC; envolventes y magnitudes no contractuales."} | {"material":true,"document":true,"quantities":true,"containerGuid":"3ztlotcerHPueDgxP84R6z","containerName":"Planta baja"} | {"id":"architecture","name":"Arquitectura"} | {"profileId":"block_masonry","name":"Fábrica de bloques · acabado mineral claro","materialName":"Bloque hueco de hormigón de árido ligero","physicalMaterialStatus":"known","physicalMaterialSource":"ARQ-OF-20260710 · Arquitectura A101 / p. 3, A103 / p. 5, A106 / p. 8; A301Cuadro de materiales ","appearanceStatus":"criterio_visual","appearanceBasis":"Bloque hueco documentado. Apariencia mineral clara para distinguir el cerramiento; no confirma un revoco ni su espesor.","note":"La apariencia gráfica no modifica ni confirma la especificación física del material."} | {"elementId":"office_0156","ifcGuid":"2ZpqAKPJ1Vex2jolWW7UaY","ifcClass":"IfcWall","buildingId":"office","buildingName":"Edificio de oficinas","sourceDocumentId":"ARQ-OF-20260710","sourceRepresentationKind":"documentary_mesh"} | {"layerId":"architecture","layerName":"Arquitectura","role":"Muro","basis":"Clasificación por función del elemento; no modifica las especificaciones documentales."} | architecture | {"profileId":"block_masonry","name":"Fábrica de bloques · acabado mineral claro","status":"criterio_visual","basis":"Bloque hueco documentado. Apariencia mineral clara para distinguir el cerramiento; no confirma un revoco ni su espesor.","physicalMaterialUnchanged":true} | ARQ-OF-20260710 · Arquitectura A101 / p. 3, A103 / p. 5, A106 / p. 8; A301Cuadro de materiales | Dimensiones contrastadas con los planos; reconstrucción geométrica a partir de documentación de diseño. | 0.2 | Muros segmentados con huecos reales para puertas y ventanas. | Envolvente exterior controlada por la planta de arquitectura; no se han modelado individualmente todas las capas de acabado. | Registro de líneas del PDF general, envolvente de 20 × 10 m; eje local 1 al norte y acceso del lado A al oeste. Estimación de trabajo de implantación de ±0,15 m, pendiente de CAD; no constituye una precisión topográfica garantizada. | Arquitectura | ARQ-OF-20260710 · Arquitectura A101 / p. 3, A103 / p. 5, A106 / p. 8; A301Cuadro de materiales | 285.95 | Arquitectura | Fábrica de bloques · acabado mineral claro | block_masonry | [0.843137,0.823529,0.772549] | 0.96 | 0 | Bloque hueco documentado. Apariencia mineral clara para distinguir el cerramiento; no confirma un revoco ni su espesor. | Arquitectura; BIM · Arquitectura | El plano general de 2026-07-31 mantiene el edificio de oficinas de 200 m², mientras documentación anterior indica su supresión. Se conserva lo dibujado, pendiente de confirmación de la propiedad y del equipo de diseño.
Edificio de oficinas · Fábrica de bloques huecos de hormigón de 200 mm · eje B · tramo 35 | Planos de arquitectura del edificio de oficinas | Bloque hueco de hormigón de árido ligero | 1.5 × 0.2 × 1.1 | 288.25 | 289.35 | 0.33 | office_0157 | yes | 0.402442 | 1.51326 | 1.1 | 4.34 | 0.33 | office | Edificio de oficinas | {"name":"Bloque hueco de hormigón de árido ligero","source":"ARQ-OF-20260710 · Arquitectura A101 / p. 3, A103 / p. 5, A106 / p. 8; A301Cuadro de materiales ","status":"known"} | {"documented":[{"label":"Espesor del muro","value":0.2,"unit":"m","source":"ARQ-OF-20260710 · Arquitectura A101 / p. 3, A103 / p. 5, A106 / p. 8; A301Cuadro de materiales ","status":"documentado"}],"geometry":[{"label":"Dimensiones de la caja local del elemento (X, Y, Z)","value":"1.5 × 0.2 × 1.1","unit":"m","source":"Malla triangulada del elemento en ejes locales del edificio","status":"derivado"},{"label":"Cota mínima absoluta de la malla","value":288.25,"unit":"m","source":"Malla de proyecto y origen altimétrico 285 m","status":"derivado"},{"label":"Cota máxima absoluta de la malla","value":289.35,"unit":"m","source":"Malla de proyecto y origen altimétrico 285 m","status":"derivado"},{"label":"Volumen geométrico bruto","value":0.33,"unit":"m³","source":"Malla cerrada del elemento","status":"derivado"}],"notes":["Las dimensiones documentadas proceden de anotaciones o cuadros; la caja y el volumen se calculan a partir de la malla.","El volumen es exclusivamente geométrico y bruto; no representa una medición neta de material ni una cantidad de compra."]} | {"documentId":"ARQ-OF-20260710","title":"Planos de arquitectura del edificio de oficinas","date":"2026-07-10","sheet":"Arquitectura A101 / p. 3, A103 / p. 5, A106 / p. 8; A301Cuadro de materiales "} | ["El plano general de 2026-07-31 mantiene el edificio de oficinas de 200 m², mientras documentación anterior indica su supresión. Se conserva lo dibujado, pendiente de confirmación de la propiedad y del equipo de diseño.","Envolvente exterior controlada por la planta de arquitectura; no se han modelado individualmente todas las capas de acabado.","Registro de líneas del PDF general, envolvente de 20 × 10 m; eje local 1 al norte y acceso del lado A al oeste. Estimación de trabajo de implantación de ±0,15 m, pendiente de CAD; no constituye una precisión topográfica garantizada."] | {"horizontalStatus":"derivado","verticalStatus":"derivado","baseElevationM":285.95,"note":"Registro de líneas del PDF general, envolvente de 20 × 10 m; eje local 1 al norte y acceso del lado A al oeste. Estimación de trabajo de implantación de ±0,15 m, pendiente de CAD; no constituye una precisión topográfica garantizada."} | {"Pset_WallCommon":{"IsExternal":{"value":true,"source":"ARQ-OF-20260710 · A101, A103 y alzados; elemento de la envolvente exterior identificada en planta","status":"known"}}} | {"boundingBoxM":{"min":[25.644101,79.865755,3.25],"max":[26.046543,81.379017,4.35]},"extentsM":[0.402442,1.513262,1.1],"meshSurfaceM2":4.339999,"meshVolumeM3":0.33,"closedSolid":true,"basis":"Geometría triangulada releída del IFC; envolventes y magnitudes no contractuales."} | {"material":true,"document":true,"quantities":true,"containerGuid":"3ztlotcerHPueDgxP84R6z","containerName":"Planta baja"} | {"id":"architecture","name":"Arquitectura"} | {"profileId":"block_masonry","name":"Fábrica de bloques · acabado mineral claro","materialName":"Bloque hueco de hormigón de árido ligero","physicalMaterialStatus":"known","physicalMaterialSource":"ARQ-OF-20260710 · Arquitectura A101 / p. 3, A103 / p. 5, A106 / p. 8; A301Cuadro de materiales ","appearanceStatus":"criterio_visual","appearanceBasis":"Bloque hueco documentado. Apariencia mineral clara para distinguir el cerramiento; no confirma un revoco ni su espesor.","note":"La apariencia gráfica no modifica ni confirma la especificación física del material."} | {"elementId":"office_0157","ifcGuid":"0vMBJUlF9KzO13ZUnISqBh","ifcClass":"IfcWall","buildingId":"office","buildingName":"Edificio de oficinas","sourceDocumentId":"ARQ-OF-20260710","sourceRepresentationKind":"documentary_mesh"} | {"layerId":"architecture","layerName":"Arquitectura","role":"Muro","basis":"Clasificación por función del elemento; no modifica las especificaciones documentales."} | architecture | {"profileId":"block_masonry","name":"Fábrica de bloques · acabado mineral claro","status":"criterio_visual","basis":"Bloque hueco documentado. Apariencia mineral clara para distinguir el cerramiento; no confirma un revoco ni su espesor.","physicalMaterialUnchanged":true} | ARQ-OF-20260710 · Arquitectura A101 / p. 3, A103 / p. 5, A106 / p. 8; A301Cuadro de materiales | Dimensiones contrastadas con los planos; reconstrucción geométrica a partir de documentación de diseño. | 0.2 | Muros segmentados con huecos reales para puertas y ventanas. | Envolvente exterior controlada por la planta de arquitectura; no se han modelado individualmente todas las capas de acabado. | Registro de líneas del PDF general, envolvente de 20 × 10 m; eje local 1 al norte y acceso del lado A al oeste. Estimación de trabajo de implantación de ±0,15 m, pendiente de CAD; no constituye una precisión topográfica garantizada. | Arquitectura | ARQ-OF-20260710 · Arquitectura A101 / p. 3, A103 / p. 5, A106 / p. 8; A301Cuadro de materiales | 285.95 | Arquitectura | Fábrica de bloques · acabado mineral claro | block_masonry | [0.843137,0.823529,0.772549] | 0.96 | 0 | Bloque hueco documentado. Apariencia mineral clara para distinguir el cerramiento; no confirma un revoco ni su espesor. | Arquitectura; BIM · Arquitectura | El plano general de 2026-07-31 mantiene el edificio de oficinas de 200 m², mientras documentación anterior indica su supresión. Se conserva lo dibujado, pendiente de confirmación de la propiedad y del equipo de diseño.
Edificio de oficinas · Fábrica de bloques huecos de hormigón de 200 mm · eje B · tramo 36 | Planos de arquitectura del edificio de oficinas | Bloque hueco de hormigón de árido ligero | 1.5 × 0.2 × 1.6 | 289.35 | 290.95 | 0.48 | office_0158 | yes | 0.402442 | 1.51326 | 1.6 | 6.04 | 0.48 | office | Edificio de oficinas | {"name":"Bloque hueco de hormigón de árido ligero","source":"ARQ-OF-20260710 · Arquitectura A101 / p. 3, A103 / p. 5, A106 / p. 8; A301Cuadro de materiales ","status":"known"} | {"documented":[{"label":"Espesor del muro","value":0.2,"unit":"m","source":"ARQ-OF-20260710 · Arquitectura A101 / p. 3, A103 / p. 5, A106 / p. 8; A301Cuadro de materiales ","status":"documentado"}],"geometry":[{"label":"Dimensiones de la caja local del elemento (X, Y, Z)","value":"1.5 × 0.2 × 1.6","unit":"m","source":"Malla triangulada del elemento en ejes locales del edificio","status":"derivado"},{"label":"Cota mínima absoluta de la malla","value":289.35,"unit":"m","source":"Malla de proyecto y origen altimétrico 285 m","status":"derivado"},{"label":"Cota máxima absoluta de la malla","value":290.95,"unit":"m","source":"Malla de proyecto y origen altimétrico 285 m","status":"derivado"},{"label":"Volumen geométrico bruto","value":0.48,"unit":"m³","source":"Malla cerrada del elemento","status":"derivado"}],"notes":["Las dimensiones documentadas proceden de anotaciones o cuadros; la caja y el volumen se calculan a partir de la malla.","El volumen es exclusivamente geométrico y bruto; no representa una medición neta de material ni una cantidad de compra."]} | {"documentId":"ARQ-OF-20260710","title":"Planos de arquitectura del edificio de oficinas","date":"2026-07-10","sheet":"Arquitectura A101 / p. 3, A103 / p. 5, A106 / p. 8; A301Cuadro de materiales "} | ["El plano general de 2026-07-31 mantiene el edificio de oficinas de 200 m², mientras documentación anterior indica su supresión. Se conserva lo dibujado, pendiente de confirmación de la propiedad y del equipo de diseño.","Envolvente exterior controlada por la planta de arquitectura; no se han modelado individualmente todas las capas de acabado.","Registro de líneas del PDF general, envolvente de 20 × 10 m; eje local 1 al norte y acceso del lado A al oeste. Estimación de trabajo de implantación de ±0,15 m, pendiente de CAD; no constituye una precisión topográfica garantizada."] | {"horizontalStatus":"derivado","verticalStatus":"derivado","baseElevationM":285.95,"note":"Registro de líneas del PDF general, envolvente de 20 × 10 m; eje local 1 al norte y acceso del lado A al oeste. Estimación de trabajo de implantación de ±0,15 m, pendiente de CAD; no constituye una precisión topográfica garantizada."} | {"Pset_WallCommon":{"IsExternal":{"value":true,"source":"ARQ-OF-20260710 · A101, A103 y alzados; elemento de la envolvente exterior identificada en planta","status":"known"}}} | {"boundingBoxM":{"min":[25.644101,79.865755,4.35],"max":[26.046543,81.379017,5.95]},"extentsM":[0.402442,1.513262,1.6],"meshSurfaceM2":6.039998,"meshVolumeM3":0.48,"closedSolid":true,"basis":"Geometría triangulada releída del IFC; envolventes y magnitudes no contractuales."} | {"material":true,"document":true,"quantities":true,"containerGuid":"3ztlotcerHPueDgxP84R6z","containerName":"Planta baja"} | {"id":"architecture","name":"Arquitectura"} | {"profileId":"block_masonry","name":"Fábrica de bloques · acabado mineral claro","materialName":"Bloque hueco de hormigón de árido ligero","physicalMaterialStatus":"known","physicalMaterialSource":"ARQ-OF-20260710 · Arquitectura A101 / p. 3, A103 / p. 5, A106 / p. 8; A301Cuadro de materiales ","appearanceStatus":"criterio_visual","appearanceBasis":"Bloque hueco documentado. Apariencia mineral clara para distinguir el cerramiento; no confirma un revoco ni su espesor.","note":"La apariencia gráfica no modifica ni confirma la especificación física del material."} | {"elementId":"office_0158","ifcGuid":"2PnDmhb$9Mde$i7q7GNXpy","ifcClass":"IfcWall","buildingId":"office","buildingName":"Edificio de oficinas","sourceDocumentId":"ARQ-OF-20260710","sourceRepresentationKind":"documentary_mesh"} | {"layerId":"architecture","layerName":"Arquitectura","role":"Muro","basis":"Clasificación por función del elemento; no modifica las especificaciones documentales."} | architecture | {"profileId":"block_masonry","name":"Fábrica de bloques · acabado mineral claro","status":"criterio_visual","basis":"Bloque hueco documentado. Apariencia mineral clara para distinguir el cerramiento; no confirma un revoco ni su espesor.","physicalMaterialUnchanged":true} | ARQ-OF-20260710 · Arquitectura A101 / p. 3, A103 / p. 5, A106 / p. 8; A301Cuadro de materiales | Dimensiones contrastadas con los planos; reconstrucción geométrica a partir de documentación de diseño. | 0.2 | Muros segmentados con huecos reales para puertas y ventanas. | Envolvente exterior controlada por la planta de arquitectura; no se han modelado individualmente todas las capas de acabado. | Registro de líneas del PDF general, envolvente de 20 × 10 m; eje local 1 al norte y acceso del lado A al oeste. Estimación de trabajo de implantación de ±0,15 m, pendiente de CAD; no constituye una precisión topográfica garantizada. | Arquitectura | ARQ-OF-20260710 · Arquitectura A101 / p. 3, A103 / p. 5, A106 / p. 8; A301Cuadro de materiales | 285.95 | Arquitectura | Fábrica de bloques · acabado mineral claro | block_masonry | [0.843137,0.823529,0.772549] | 0.96 | 0 | Bloque hueco documentado. Apariencia mineral clara para distinguir el cerramiento; no confirma un revoco ni su espesor. | Arquitectura; BIM · Arquitectura | El plano general de 2026-07-31 mantiene el edificio de oficinas de 200 m², mientras documentación anterior indica su supresión. Se conserva lo dibujado, pendiente de confirmación de la propiedad y del equipo de diseño.
Edificio de oficinas · Fábrica de bloques huecos de hormigón de 200 mm · eje B · tramo 37 | Planos de arquitectura del edificio de oficinas | Bloque hueco de hormigón de árido ligero | 1.8 × 0.2 × 1.1 | 285.95 | 287.05 | 0.396 | office_0159 | yes | 0.443303 | 1.81047 | 1.1 | 5.12 | 0.396 | office | Edificio de oficinas | {"name":"Bloque hueco de hormigón de árido ligero","source":"ARQ-OF-20260710 · Arquitectura A101 / p. 3, A103 / p. 5, A106 / p. 8; A301Cuadro de materiales ","status":"known"} | {"documented":[{"label":"Espesor del muro","value":0.2,"unit":"m","source":"ARQ-OF-20260710 · Arquitectura A101 / p. 3, A103 / p. 5, A106 / p. 8; A301Cuadro de materiales ","status":"documentado"}],"geometry":[{"label":"Dimensiones de la caja local del elemento (X, Y, Z)","value":"1.8 × 0.2 × 1.1","unit":"m","source":"Malla triangulada del elemento en ejes locales del edificio","status":"derivado"},{"label":"Cota mínima absoluta de la malla","value":285.95,"unit":"m","source":"Malla de proyecto y origen altimétrico 285 m","status":"derivado"},{"label":"Cota máxima absoluta de la malla","value":287.05,"unit":"m","source":"Malla de proyecto y origen altimétrico 285 m","status":"derivado"},{"label":"Volumen geométrico bruto","value":0.396,"unit":"m³","source":"Malla cerrada del elemento","status":"derivado"}],"notes":["Las dimensiones documentadas proceden de anotaciones o cuadros; la caja y el volumen se calculan a partir de la malla.","El volumen es exclusivamente geométrico y bruto; no representa una medición neta de material ni una cantidad de compra."]} | {"documentId":"ARQ-OF-20260710","title":"Planos de arquitectura del edificio de oficinas","date":"2026-07-10","sheet":"Arquitectura A101 / p. 3, A103 / p. 5, A106 / p. 8; A301Cuadro de materiales "} | ["El plano general de 2026-07-31 mantiene el edificio de oficinas de 200 m², mientras documentación anterior indica su supresión. Se conserva lo dibujado, pendiente de confirmación de la propiedad y del equipo de diseño.","Envolvente exterior controlada por la planta de arquitectura; no se han modelado individualmente todas las capas de acabado.","Registro de líneas del PDF general, envolvente de 20 × 10 m; eje local 1 al norte y acceso del lado A al oeste. Estimación de trabajo de implantación de ±0,15 m, pendiente de CAD; no constituye una precisión topográfica garantizada."] | {"horizontalStatus":"derivado","verticalStatus":"derivado","baseElevationM":285.95,"note":"Registro de líneas del PDF general, envolvente de 20 × 10 m; eje local 1 al norte y acceso del lado A al oeste. Estimación de trabajo de implantación de ±0,15 m, pendiente de CAD; no constituye una precisión topográfica garantizada."} | {"Pset_WallCommon":{"IsExternal":{"value":true,"source":"ARQ-OF-20260710 · A101, A103 y alzados; elemento de la envolvente exterior identificada en planta","status":"known"}}} | {"boundingBoxM":{"min":[25.398934,78.082529,0.95],"max":[25.842237,79.892996,2.05]},"extentsM":[0.443303,1.810467,1.1],"meshSurfaceM2":5.120001,"meshVolumeM3":0.396,"closedSolid":true,"basis":"Geometría triangulada releída del IFC; envolventes y magnitudes no contractuales."} | {"material":true,"document":true,"quantities":true,"containerGuid":"3ztlotcerHPueDgxP84R6z","containerName":"Planta baja"} | {"id":"architecture","name":"Arquitectura"} | {"profileId":"block_masonry","name":"Fábrica de bloques · acabado mineral claro","materialName":"Bloque hueco de hormigón de árido ligero","physicalMaterialStatus":"known","physicalMaterialSource":"ARQ-OF-20260710 · Arquitectura A101 / p. 3, A103 / p. 5, A106 / p. 8; A301Cuadro de materiales ","appearanceStatus":"criterio_visual","appearanceBasis":"Bloque hueco documentado. Apariencia mineral clara para distinguir el cerramiento; no confirma un revoco ni su espesor.","note":"La apariencia gráfica no modifica ni confirma la especificación física del material."} | {"elementId":"office_0159","ifcGuid":"38AJeUR7LNCeqpgwJk9ecq","ifcClass":"IfcWall","buildingId":"office","buildingName":"Edificio de oficinas","sourceDocumentId":"ARQ-OF-20260710","sourceRepresentationKind":"documentary_mesh"} | {"layerId":"architecture","layerName":"Arquitectura","role":"Muro","basis":"Clasificación por función del elemento; no modifica las especificaciones documentales."} | architecture | {"profileId":"block_masonry","name":"Fábrica de bloques · acabado mineral claro","status":"criterio_visual","basis":"Bloque hueco documentado. Apariencia mineral clara para distinguir el cerramiento; no confirma un revoco ni su espesor.","physicalMaterialUnchanged":true} | ARQ-OF-20260710 · Arquitectura A101 / p. 3, A103 / p. 5, A106 / p. 8; A301Cuadro de materiales | Dimensiones contrastadas con los planos; reconstrucción geométrica a partir de documentación de diseño. | 0.2 | Muros segmentados con huecos reales para puertas y ventanas. | Envolvente exterior controlada por la planta de arquitectura; no se han modelado individualmente todas las capas de acabado. | Registro de líneas del PDF general, envolvente de 20 × 10 m; eje local 1 al norte y acceso del lado A al oeste. Estimación de trabajo de implantación de ±0,15 m, pendiente de CAD; no constituye una precisión topográfica garantizada. | Arquitectura | ARQ-OF-20260710 · Arquitectura A101 / p. 3, A103 / p. 5, A106 / p. 8; A301Cuadro de materiales | 285.95 | Arquitectura | Fábrica de bloques · acabado mineral claro | block_masonry | [0.843137,0.823529,0.772549] | 0.96 | 0 | Bloque hueco documentado. Apariencia mineral clara para distinguir el cerramiento; no confirma un revoco ni su espesor. | Arquitectura; BIM · Arquitectura | El plano general de 2026-07-31 mantiene el edificio de oficinas de 200 m², mientras documentación anterior indica su supresión. Se conserva lo dibujado, pendiente de confirmación de la propiedad y del equipo de diseño.
Edificio de oficinas · Fábrica de bloques huecos de hormigón de 200 mm · eje B · tramo 38 | Planos de arquitectura del edificio de oficinas | Bloque hueco de hormigón de árido ligero | 1.8 × 0.2 × 1.2 | 287.05 | 288.25 | 0.432 | office_0160 | yes | 0.443303 | 1.81047 | 1.2 | 5.52 | 0.432 | office | Edificio de oficinas | {"name":"Bloque hueco de hormigón de árido ligero","source":"ARQ-OF-20260710 · Arquitectura A101 / p. 3, A103 / p. 5, A106 / p. 8; A301Cuadro de materiales ","status":"known"} | {"documented":[{"label":"Espesor del muro","value":0.2,"unit":"m","source":"ARQ-OF-20260710 · Arquitectura A101 / p. 3, A103 / p. 5, A106 / p. 8; A301Cuadro de materiales ","status":"documentado"}],"geometry":[{"label":"Dimensiones de la caja local del elemento (X, Y, Z)","value":"1.8 × 0.2 × 1.2","unit":"m","source":"Malla triangulada del elemento en ejes locales del edificio","status":"derivado"},{"label":"Cota mínima absoluta de la malla","value":287.05,"unit":"m","source":"Malla de proyecto y origen altimétrico 285 m","status":"derivado"},{"label":"Cota máxima absoluta de la malla","value":288.25,"unit":"m","source":"Malla de proyecto y origen altimétrico 285 m","status":"derivado"},{"label":"Volumen geométrico bruto","value":0.432,"unit":"m³","source":"Malla cerrada del elemento","status":"derivado"}],"notes":["Las dimensiones documentadas proceden de anotaciones o cuadros; la caja y el volumen se calculan a partir de la malla.","El volumen es exclusivamente geométrico y bruto; no representa una medición neta de material ni una cantidad de compra."]} | {"documentId":"ARQ-OF-20260710","title":"Planos de arquitectura del edificio de oficinas","date":"2026-07-10","sheet":"Arquitectura A101 / p. 3, A103 / p. 5, A106 / p. 8; A301Cuadro de materiales "} | ["El plano general de 2026-07-31 mantiene el edificio de oficinas de 200 m², mientras documentación anterior indica su supresión. Se conserva lo dibujado, pendiente de confirmación de la propiedad y del equipo de diseño.","Envolvente exterior controlada por la planta de arquitectura; no se han modelado individualmente todas las capas de acabado.","Registro de líneas del PDF general, envolvente de 20 × 10 m; eje local 1 al norte y acceso del lado A al oeste. Estimación de trabajo de implantación de ±0,15 m, pendiente de CAD; no constituye una precisión topográfica garantizada."] | {"horizontalStatus":"derivado","verticalStatus":"derivado","baseElevationM":285.95,"note":"Registro de líneas del PDF general, envolvente de 20 × 10 m; eje local 1 al norte y acceso del lado A al oeste. Estimación de trabajo de implantación de ±0,15 m, pendiente de CAD; no constituye una precisión topográfica garantizada."} | {"Pset_WallCommon":{"IsExternal":{"value":true,"source":"ARQ-OF-20260710 · A101, A103 y alzados; elemento de la envolvente exterior identificada en planta","status":"known"}}} | {"boundingBoxM":{"min":[25.398934,78.082529,2.05],"max":[25.842237,79.892996,3.25]},"extentsM":[0.443303,1.810467,1.2],"meshSurfaceM2":5.520001,"meshVolumeM3":0.432,"closedSolid":true,"basis":"Geometría triangulada releída del IFC; envolventes y magnitudes no contractuales."} | {"material":true,"document":true,"quantities":true,"containerGuid":"3ztlotcerHPueDgxP84R6z","containerName":"Planta baja"} | {"id":"architecture","name":"Arquitectura"} | {"profileId":"block_masonry","name":"Fábrica de bloques · acabado mineral claro","materialName":"Bloque hueco de hormigón de árido ligero","physicalMaterialStatus":"known","physicalMaterialSource":"ARQ-OF-20260710 · Arquitectura A101 / p. 3, A103 / p. 5, A106 / p. 8; A301Cuadro de materiales ","appearanceStatus":"criterio_visual","appearanceBasis":"Bloque hueco documentado. Apariencia mineral clara para distinguir el cerramiento; no confirma un revoco ni su espesor.","note":"La apariencia gráfica no modifica ni confirma la especificación física del material."} | {"elementId":"office_0160","ifcGuid":"0QeqyciPrQFxVhOwTuDlin","ifcClass":"IfcWall","buildingId":"office","buildingName":"Edificio de oficinas","sourceDocumentId":"ARQ-OF-20260710","sourceRepresentationKind":"documentary_mesh"} | {"layerId":"architecture","layerName":"Arquitectura","role":"Muro","basis":"Clasificación por función del elemento; no modifica las especificaciones documentales."} | architecture | {"profileId":"block_masonry","name":"Fábrica de bloques · acabado mineral claro","status":"criterio_visual","basis":"Bloque hueco documentado. Apariencia mineral clara para distinguir el cerramiento; no confirma un revoco ni su espesor.","physicalMaterialUnchanged":true} | ARQ-OF-20260710 · Arquitectura A101 / p. 3, A103 / p. 5, A106 / p. 8; A301Cuadro de materiales | Dimensiones contrastadas con los planos; reconstrucción geométrica a partir de documentación de diseño. | 0.2 | Muros segmentados con huecos reales para puertas y ventanas. | Envolvente exterior controlada por la planta de arquitectura; no se han modelado individualmente todas las capas de acabado. | Registro de líneas del PDF general, envolvente de 20 × 10 m; eje local 1 al norte y acceso del lado A al oeste. Estimación de trabajo de implantación de ±0,15 m, pendiente de CAD; no constituye una precisión topográfica garantizada. | Arquitectura | ARQ-OF-20260710 · Arquitectura A101 / p. 3, A103 / p. 5, A106 / p. 8; A301Cuadro de materiales | 285.95 | Arquitectura | Fábrica de bloques · acabado mineral claro | block_masonry | [0.843137,0.823529,0.772549] | 0.96 | 0 | Bloque hueco documentado. Apariencia mineral clara para distinguir el cerramiento; no confirma un revoco ni su espesor. | Arquitectura; BIM · Arquitectura | El plano general de 2026-07-31 mantiene el edificio de oficinas de 200 m², mientras documentación anterior indica su supresión. Se conserva lo dibujado, pendiente de confirmación de la propiedad y del equipo de diseño.
Edificio de oficinas · Fábrica de bloques huecos de hormigón de 200 mm · eje B · tramo 39 | Planos de arquitectura del edificio de oficinas | Bloque hueco de hormigón de árido ligero | 1.8 × 0.2 × 1.1 | 288.25 | 289.35 | 0.396 | office_0161 | yes | 0.443303 | 1.81047 | 1.1 | 5.12 | 0.396 | office | Edificio de oficinas | {"name":"Bloque hueco de hormigón de árido ligero","source":"ARQ-OF-20260710 · Arquitectura A101 / p. 3, A103 / p. 5, A106 / p. 8; A301Cuadro de materiales ","status":"known"} | {"documented":[{"label":"Espesor del muro","value":0.2,"unit":"m","source":"ARQ-OF-20260710 · Arquitectura A101 / p. 3, A103 / p. 5, A106 / p. 8; A301Cuadro de materiales ","status":"documentado"}],"geometry":[{"label":"Dimensiones de la caja local del elemento (X, Y, Z)","value":"1.8 × 0.2 × 1.1","unit":"m","source":"Malla triangulada del elemento en ejes locales del edificio","status":"derivado"},{"label":"Cota mínima absoluta de la malla","value":288.25,"unit":"m","source":"Malla de proyecto y origen altimétrico 285 m","status":"derivado"},{"label":"Cota máxima absoluta de la malla","value":289.35,"unit":"m","source":"Malla de proyecto y origen altimétrico 285 m","status":"derivado"},{"label":"Volumen geométrico bruto","value":0.396,"unit":"m³","source":"Malla cerrada del elemento","status":"derivado"}],"notes":["Las dimensiones documentadas proceden de anotaciones o cuadros; la caja y el volumen se calculan a partir de la malla.","El volumen es exclusivamente geométrico y bruto; no representa una medición neta de material ni una cantidad de compra."]} | {"documentId":"ARQ-OF-20260710","title":"Planos de arquitectura del edificio de oficinas","date":"2026-07-10","sheet":"Arquitectura A101 / p. 3, A103 / p. 5, A106 / p. 8; A301Cuadro de materiales "} | ["El plano general de 2026-07-31 mantiene el edificio de oficinas de 200 m², mientras documentación anterior indica su supresión. Se conserva lo dibujado, pendiente de confirmación de la propiedad y del equipo de diseño.","Envolvente exterior controlada por la planta de arquitectura; no se han modelado individualmente todas las capas de acabado.","Registro de líneas del PDF general, envolvente de 20 × 10 m; eje local 1 al norte y acceso del lado A al oeste. Estimación de trabajo de implantación de ±0,15 m, pendiente de CAD; no constituye una precisión topográfica garantizada."] | {"horizontalStatus":"derivado","verticalStatus":"derivado","baseElevationM":285.95,"note":"Registro de líneas del PDF general, envolvente de 20 × 10 m; eje local 1 al norte y acceso del lado A al oeste. Estimación de trabajo de implantación de ±0,15 m, pendiente de CAD; no constituye una precisión topográfica garantizada."} | {"Pset_WallCommon":{"IsExternal":{"value":true,"source":"ARQ-OF-20260710 · A101, A103 y alzados; elemento de la envolvente exterior identificada en planta","status":"known"}}} | {"boundingBoxM":{"min":[25.398934,78.082529,3.25],"max":[25.842237,79.892996,4.35]},"extentsM":[0.443303,1.810467,1.1],"meshSurfaceM2":5.120001,"meshVolumeM3":0.396,"closedSolid":true,"basis":"Geometría triangulada releída del IFC; envolventes y magnitudes no contractuales."} | {"material":true,"document":true,"quantities":true,"containerGuid":"3ztlotcerHPueDgxP84R6z","containerName":"Planta baja"} | {"id":"architecture","name":"Arquitectura"} | {"profileId":"block_masonry","name":"Fábrica de bloques · acabado mineral claro","materialName":"Bloque hueco de hormigón de árido ligero","physicalMaterialStatus":"known","physicalMaterialSource":"ARQ-OF-20260710 · Arquitectura A101 / p. 3, A103 / p. 5, A106 / p. 8; A301Cuadro de materiales ","appearanceStatus":"criterio_visual","appearanceBasis":"Bloque hueco documentado. Apariencia mineral clara para distinguir el cerramiento; no confirma un revoco ni su espesor.","note":"La apariencia gráfica no modifica ni confirma la especificación física del material."} | {"elementId":"office_0161","ifcGuid":"1fRYc6k95I5ghyQ_zPgoYk","ifcClass":"IfcWall","buildingId":"office","buildingName":"Edificio de oficinas","sourceDocumentId":"ARQ-OF-20260710","sourceRepresentationKind":"documentary_mesh"} | {"layerId":"architecture","layerName":"Arquitectura","role":"Muro","basis":"Clasificación por función del elemento; no modifica las especificaciones documentales."} | architecture | {"profileId":"block_masonry","name":"Fábrica de bloques · acabado mineral claro","status":"criterio_visual","basis":"Bloque hueco documentado. Apariencia mineral clara para distinguir el cerramiento; no confirma un revoco ni su espesor.","physicalMaterialUnchanged":true} | ARQ-OF-20260710 · Arquitectura A101 / p. 3, A103 / p. 5, A106 / p. 8; A301Cuadro de materiales | Dimensiones contrastadas con los planos; reconstrucción geométrica a partir de documentación de diseño. | 0.2 | Muros segmentados con huecos reales para puertas y ventanas. | Envolvente exterior controlada por la planta de arquitectura; no se han modelado individualmente todas las capas de acabado. | Registro de líneas del PDF general, envolvente de 20 × 10 m; eje local 1 al norte y acceso del lado A al oeste. Estimación de trabajo de implantación de ±0,15 m, pendiente de CAD; no constituye una precisión topográfica garantizada. | Arquitectura | ARQ-OF-20260710 · Arquitectura A101 / p. 3, A103 / p. 5, A106 / p. 8; A301Cuadro de materiales | 285.95 | Arquitectura | Fábrica de bloques · acabado mineral claro | block_masonry | [0.843137,0.823529,0.772549] | 0.96 | 0 | Bloque hueco documentado. Apariencia mineral clara para distinguir el cerramiento; no confirma un revoco ni su espesor. | Arquitectura; BIM · Arquitectura | El plano general de 2026-07-31 mantiene el edificio de oficinas de 200 m², mientras documentación anterior indica su supresión. Se conserva lo dibujado, pendiente de confirmación de la propiedad y del equipo de diseño.
Edificio de oficinas · Fábrica de bloques huecos de hormigón de 200 mm · eje B · tramo 40 | Planos de arquitectura del edificio de oficinas | Bloque hueco de hormigón de árido ligero | 1.8 × 0.2 × 1.6 | 289.35 | 290.95 | 0.576 | office_0162 | yes | 0.443303 | 1.81047 | 1.6 | 7.12 | 0.576 | office | Edificio de oficinas | {"name":"Bloque hueco de hormigón de árido ligero","source":"ARQ-OF-20260710 · Arquitectura A101 / p. 3, A103 / p. 5, A106 / p. 8; A301Cuadro de materiales ","status":"known"} | {"documented":[{"label":"Espesor del muro","value":0.2,"unit":"m","source":"ARQ-OF-20260710 · Arquitectura A101 / p. 3, A103 / p. 5, A106 / p. 8; A301Cuadro de materiales ","status":"documentado"}],"geometry":[{"label":"Dimensiones de la caja local del elemento (X, Y, Z)","value":"1.8 × 0.2 × 1.6","unit":"m","source":"Malla triangulada del elemento en ejes locales del edificio","status":"derivado"},{"label":"Cota mínima absoluta de la malla","value":289.35,"unit":"m","source":"Malla de proyecto y origen altimétrico 285 m","status":"derivado"},{"label":"Cota máxima absoluta de la malla","value":290.95,"unit":"m","source":"Malla de proyecto y origen altimétrico 285 m","status":"derivado"},{"label":"Volumen geométrico bruto","value":0.576,"unit":"m³","source":"Malla cerrada del elemento","status":"derivado"}],"notes":["Las dimensiones documentadas proceden de anotaciones o cuadros; la caja y el volumen se calculan a partir de la malla.","El volumen es exclusivamente geométrico y bruto; no representa una medición neta de material ni una cantidad de compra."]} | {"documentId":"ARQ-OF-20260710","title":"Planos de arquitectura del edificio de oficinas","date":"2026-07-10","sheet":"Arquitectura A101 / p. 3, A103 / p. 5, A106 / p. 8; A301Cuadro de materiales "} | ["El plano general de 2026-07-31 mantiene el edificio de oficinas de 200 m², mientras documentación anterior indica su supresión. Se conserva lo dibujado, pendiente de confirmación de la propiedad y del equipo de diseño.","Envolvente exterior controlada por la planta de arquitectura; no se han modelado individualmente todas las capas de acabado.","Registro de líneas del PDF general, envolvente de 20 × 10 m; eje local 1 al norte y acceso del lado A al oeste. Estimación de trabajo de implantación de ±0,15 m, pendiente de CAD; no constituye una precisión topográfica garantizada."] | {"horizontalStatus":"derivado","verticalStatus":"derivado","baseElevationM":285.95,"note":"Registro de líneas del PDF general, envolvente de 20 × 10 m; eje local 1 al norte y acceso del lado A al oeste. Estimación de trabajo de implantación de ±0,15 m, pendiente de CAD; no constituye una precisión topográfica garantizada."} | {"Pset_WallCommon":{"IsExternal":{"value":true,"source":"ARQ-OF-20260710 · A101, A103 y alzados; elemento de la envolvente exterior identificada en planta","status":"known"}}} | {"boundingBoxM":{"min":[25.398934,78.082529,4.35],"max":[25.842237,79.892996,5.95]},"extentsM":[0.443303,1.810467,1.6],"meshSurfaceM2":7.120001,"meshVolumeM3":0.576,"closedSolid":true,"basis":"Geometría triangulada releída del IFC; envolventes y magnitudes no contractuales."} | {"material":true,"document":true,"quantities":true,"containerGuid":"3ztlotcerHPueDgxP84R6z","containerName":"Planta baja"} | {"id":"architecture","name":"Arquitectura"} | {"profileId":"block_masonry","name":"Fábrica de bloques · acabado mineral claro","materialName":"Bloque hueco de hormigón de árido ligero","physicalMaterialStatus":"known","physicalMaterialSource":"ARQ-OF-20260710 · Arquitectura A101 / p. 3, A103 / p. 5, A106 / p. 8; A301Cuadro de materiales ","appearanceStatus":"criterio_visual","appearanceBasis":"Bloque hueco documentado. Apariencia mineral clara para distinguir el cerramiento; no confirma un revoco ni su espesor.","note":"La apariencia gráfica no modifica ni confirma la especificación física del material."} | {"elementId":"office_0162","ifcGuid":"1p7hXqSl5RcOqM0KN30aVi","ifcClass":"IfcWall","buildingId":"office","buildingName":"Edificio de oficinas","sourceDocumentId":"ARQ-OF-20260710","sourceRepresentationKind":"documentary_mesh"} | {"layerId":"architecture","layerName":"Arquitectura","role":"Muro","basis":"Clasificación por función del elemento; no modifica las especificaciones documentales."} | architecture | {"profileId":"block_masonry","name":"Fábrica de bloques · acabado mineral claro","status":"criterio_visual","basis":"Bloque hueco documentado. Apariencia mineral clara para distinguir el cerramiento; no confirma un revoco ni su espesor.","physicalMaterialUnchanged":true} | ARQ-OF-20260710 · Arquitectura A101 / p. 3, A103 / p. 5, A106 / p. 8; A301Cuadro de materiales | Dimensiones contrastadas con los planos; reconstrucción geométrica a partir de documentación de diseño. | 0.2 | Muros segmentados con huecos reales para puertas y ventanas. | Envolvente exterior controlada por la planta de arquitectura; no se han modelado individualmente todas las capas de acabado. | Registro de líneas del PDF general, envolvente de 20 × 10 m; eje local 1 al norte y acceso del lado A al oeste. Estimación de trabajo de implantación de ±0,15 m, pendiente de CAD; no constituye una precisión topográfica garantizada. | Arquitectura | ARQ-OF-20260710 · Arquitectura A101 / p. 3, A103 / p. 5, A106 / p. 8; A301Cuadro de materiales | 285.95 | Arquitectura | Fábrica de bloques · acabado mineral claro | block_masonry | [0.843137,0.823529,0.772549] | 0.96 | 0 | Bloque hueco documentado. Apariencia mineral clara para distinguir el cerramiento; no confirma un revoco ni su espesor. | Arquitectura; BIM · Arquitectura | El plano general de 2026-07-31 mantiene el edificio de oficinas de 200 m², mientras documentación anterior indica su supresión. Se conserva lo dibujado, pendiente de confirmación de la propiedad y del equipo de diseño.
Edificio de oficinas · Fábrica de bloques huecos de hormigón de 200 mm · eje B · tramo 41 | Planos de arquitectura del edificio de oficinas | Bloque hueco de hormigón de árido ligero | 0.6 × 0.2 × 1.1 | 285.95 | 287.05 | 0.132 | office_0163 | yes | 0.279859 | 0.621649 | 1.1 | 2 | 0.132 | office | Edificio de oficinas | {"name":"Bloque hueco de hormigón de árido ligero","source":"ARQ-OF-20260710 · Arquitectura A101 / p. 3, A103 / p. 5, A106 / p. 8; A301Cuadro de materiales ","status":"known"} | {"documented":[{"label":"Espesor del muro","value":0.2,"unit":"m","source":"ARQ-OF-20260710 · Arquitectura A101 / p. 3, A103 / p. 5, A106 / p. 8; A301Cuadro de materiales ","status":"documentado"}],"geometry":[{"label":"Dimensiones de la caja local del elemento (X, Y, Z)","value":"0.6 × 0.2 × 1.1","unit":"m","source":"Malla triangulada del elemento en ejes locales del edificio","status":"derivado"},{"label":"Cota mínima absoluta de la malla","value":285.95,"unit":"m","source":"Malla de proyecto y origen altimétrico 285 m","status":"derivado"},{"label":"Cota máxima absoluta de la malla","value":287.05,"unit":"m","source":"Malla de proyecto y origen altimétrico 285 m","status":"derivado"},{"label":"Volumen geométrico bruto","value":0.132,"unit":"m³","source":"Malla cerrada del elemento","status":"derivado"}],"notes":["Las dimensiones documentadas proceden de anotaciones o cuadros; la caja y el volumen se calculan a partir de la malla.","El volumen es exclusivamente geométrico y bruto; no representa una medición neta de material ni una cantidad de compra."]} | {"documentId":"ARQ-OF-20260710","title":"Planos de arquitectura del edificio de oficinas","date":"2026-07-10","sheet":"Arquitectura A101 / p. 3, A103 / p. 5, A106 / p. 8; A301Cuadro de materiales "} | ["El plano general de 2026-07-31 mantiene el edificio de oficinas de 200 m², mientras documentación anterior indica su supresión. Se conserva lo dibujado, pendiente de confirmación de la propiedad y del equipo de diseño.","Envolvente exterior controlada por la planta de arquitectura; no se han modelado individualmente todas las capas de acabado.","Registro de líneas del PDF general, envolvente de 20 × 10 m; eje local 1 al norte y acceso del lado A al oeste. Estimación de trabajo de implantación de ±0,15 m, pendiente de CAD; no constituye una precisión topográfica garantizada."] | {"horizontalStatus":"derivado","verticalStatus":"derivado","baseElevationM":285.95,"note":"Registro de líneas del PDF general, envolvente de 20 × 10 m; eje local 1 al norte y acceso del lado A al oeste. Estimación de trabajo de implantación de ±0,15 m, pendiente de CAD; no constituye una precisión topográfica garantizada."} | {"Pset_WallCommon":{"IsExternal":{"value":true,"source":"ARQ-OF-20260710 · A101, A103 y alzados; elemento de la envolvente exterior identificada en planta","status":"known"}}} | {"boundingBoxM":{"min":[25.317211,77.488121,0.95],"max":[25.59707,78.10977,2.05]},"extentsM":[0.279859,0.621649,1.1],"meshSurfaceM2":2.0,"meshVolumeM3":0.132,"closedSolid":true,"basis":"Geometría triangulada releída del IFC; envolventes y magnitudes no contractuales."} | {"material":true,"document":true,"quantities":true,"containerGuid":"3ztlotcerHPueDgxP84R6z","containerName":"Planta baja"} | {"id":"architecture","name":"Arquitectura"} | {"profileId":"block_masonry","name":"Fábrica de bloques · acabado mineral claro","materialName":"Bloque hueco de hormigón de árido ligero","physicalMaterialStatus":"known","physicalMaterialSource":"ARQ-OF-20260710 · Arquitectura A101 / p. 3, A103 / p. 5, A106 / p. 8; A301Cuadro de materiales ","appearanceStatus":"criterio_visual","appearanceBasis":"Bloque hueco documentado. Apariencia mineral clara para distinguir el cerramiento; no confirma un revoco ni su espesor.","note":"La apariencia gráfica no modifica ni confirma la especificación física del material."} | {"elementId":"office_0163","ifcGuid":"1hktaioqbU8AHbv3Fw4rzB","ifcClass":"IfcWall","buildingId":"office","buildingName":"Edificio de oficinas","sourceDocumentId":"ARQ-OF-20260710","sourceRepresentationKind":"documentary_mesh"} | {"layerId":"architecture","layerName":"Arquitectura","role":"Muro","basis":"Clasificación por función del elemento; no modifica las especificaciones documentales."} | architecture | {"profileId":"block_masonry","name":"Fábrica de bloques · acabado mineral claro","status":"criterio_visual","basis":"Bloque hueco documentado. Apariencia mineral clara para distinguir el cerramiento; no confirma un revoco ni su espesor.","physicalMaterialUnchanged":true} | ARQ-OF-20260710 · Arquitectura A101 / p. 3, A103 / p. 5, A106 / p. 8; A301Cuadro de materiales | Dimensiones contrastadas con los planos; reconstrucción geométrica a partir de documentación de diseño. | 0.2 | Muros segmentados con huecos reales para puertas y ventanas. | Envolvente exterior controlada por la planta de arquitectura; no se han modelado individualmente todas las capas de acabado. | Registro de líneas del PDF general, envolvente de 20 × 10 m; eje local 1 al norte y acceso del lado A al oeste. Estimación de trabajo de implantación de ±0,15 m, pendiente de CAD; no constituye una precisión topográfica garantizada. | Arquitectura | ARQ-OF-20260710 · Arquitectura A101 / p. 3, A103 / p. 5, A106 / p. 8; A301Cuadro de materiales | 285.95 | Arquitectura | Fábrica de bloques · acabado mineral claro | block_masonry | [0.843137,0.823529,0.772549] | 0.96 | 0 | Bloque hueco documentado. Apariencia mineral clara para distinguir el cerramiento; no confirma un revoco ni su espesor. | Arquitectura; BIM · Arquitectura | El plano general de 2026-07-31 mantiene el edificio de oficinas de 200 m², mientras documentación anterior indica su supresión. Se conserva lo dibujado, pendiente de confirmación de la propiedad y del equipo de diseño.
Edificio de oficinas · Fábrica de bloques huecos de hormigón de 200 mm · eje B · tramo 42 | Planos de arquitectura del edificio de oficinas | Bloque hueco de hormigón de árido ligero | 0.6 × 0.2 × 1.6 | 289.35 | 290.95 | 0.192 | office_0164 | yes | 0.279859 | 0.621649 | 1.6 | 2.8 | 0.192 | office | Edificio de oficinas | {"name":"Bloque hueco de hormigón de árido ligero","source":"ARQ-OF-20260710 · Arquitectura A101 / p. 3, A103 / p. 5, A106 / p. 8; A301Cuadro de materiales ","status":"known"} | {"documented":[{"label":"Espesor del muro","value":0.2,"unit":"m","source":"ARQ-OF-20260710 · Arquitectura A101 / p. 3, A103 / p. 5, A106 / p. 8; A301Cuadro de materiales ","status":"documentado"}],"geometry":[{"label":"Dimensiones de la caja local del elemento (X, Y, Z)","value":"0.6 × 0.2 × 1.6","unit":"m","source":"Malla triangulada del elemento en ejes locales del edificio","status":"derivado"},{"label":"Cota mínima absoluta de la malla","value":289.35,"unit":"m","source":"Malla de proyecto y origen altimétrico 285 m","status":"derivado"},{"label":"Cota máxima absoluta de la malla","value":290.95,"unit":"m","source":"Malla de proyecto y origen altimétrico 285 m","status":"derivado"},{"label":"Volumen geométrico bruto","value":0.192,"unit":"m³","source":"Malla cerrada del elemento","status":"derivado"}],"notes":["Las dimensiones documentadas proceden de anotaciones o cuadros; la caja y el volumen se calculan a partir de la malla.","El volumen es exclusivamente geométrico y bruto; no representa una medición neta de material ni una cantidad de compra."]} | {"documentId":"ARQ-OF-20260710","title":"Planos de arquitectura del edificio de oficinas","date":"2026-07-10","sheet":"Arquitectura A101 / p. 3, A103 / p. 5, A106 / p. 8; A301Cuadro de materiales "} | ["El plano general de 2026-07-31 mantiene el edificio de oficinas de 200 m², mientras documentación anterior indica su supresión. Se conserva lo dibujado, pendiente de confirmación de la propiedad y del equipo de diseño.","Envolvente exterior controlada por la planta de arquitectura; no se han modelado individualmente todas las capas de acabado.","Registro de líneas del PDF general, envolvente de 20 × 10 m; eje local 1 al norte y acceso del lado A al oeste. Estimación de trabajo de implantación de ±0,15 m, pendiente de CAD; no constituye una precisión topográfica garantizada."] | {"horizontalStatus":"derivado","verticalStatus":"derivado","baseElevationM":285.95,"note":"Registro de líneas del PDF general, envolvente de 20 × 10 m; eje local 1 al norte y acceso del lado A al oeste. Estimación de trabajo de implantación de ±0,15 m, pendiente de CAD; no constituye una precisión topográfica garantizada."} | {"Pset_WallCommon":{"IsExternal":{"value":true,"source":"ARQ-OF-20260710 · A101, A103 y alzados; elemento de la envolvente exterior identificada en planta","status":"known"}}} | {"boundingBoxM":{"min":[25.317211,77.488121,4.35],"max":[25.59707,78.10977,5.95]},"extentsM":[0.279859,0.621649,1.6],"meshSurfaceM2":2.8,"meshVolumeM3":0.192,"closedSolid":true,"basis":"Geometría triangulada releída del IFC; envolventes y magnitudes no contractuales."} | {"material":true,"document":true,"quantities":true,"containerGuid":"3ztlotcerHPueDgxP84R6z","containerName":"Planta baja"} | {"id":"architecture","name":"Arquitectura"} | {"profileId":"block_masonry","name":"Fábrica de bloques · acabado mineral claro","materialName":"Bloque hueco de hormigón de árido ligero","physicalMaterialStatus":"known","physicalMaterialSource":"ARQ-OF-20260710 · Arquitectura A101 / p. 3, A103 / p. 5, A106 / p. 8; A301Cuadro de materiales ","appearanceStatus":"criterio_visual","appearanceBasis":"Bloque hueco documentado. Apariencia mineral clara para distinguir el cerramiento; no confirma un revoco ni su espesor.","note":"La apariencia gráfica no modifica ni confirma la especificación física del material."} | {"elementId":"office_0164","ifcGuid":"2C3rhaMuPTN8xdDDSYSjI3","ifcClass":"IfcWall","buildingId":"office","buildingName":"Edificio de oficinas","sourceDocumentId":"ARQ-OF-20260710","sourceRepresentationKind":"documentary_mesh"} | {"layerId":"architecture","layerName":"Arquitectura","role":"Muro","basis":"Clasificación por función del elemento; no modifica las especificaciones documentales."} | architecture | {"profileId":"block_masonry","name":"Fábrica de bloques · acabado mineral claro","status":"criterio_visual","basis":"Bloque hueco documentado. Apariencia mineral clara para distinguir el cerramiento; no confirma un revoco ni su espesor.","physicalMaterialUnchanged":true} | ARQ-OF-20260710 · Arquitectura A101 / p. 3, A103 / p. 5, A106 / p. 8; A301Cuadro de materiales | Dimensiones contrastadas con los planos; reconstrucción geométrica a partir de documentación de diseño. | 0.2 | Muros segmentados con huecos reales para puertas y ventanas. | Envolvente exterior controlada por la planta de arquitectura; no se han modelado individualmente todas las capas de acabado. | Registro de líneas del PDF general, envolvente de 20 × 10 m; eje local 1 al norte y acceso del lado A al oeste. Estimación de trabajo de implantación de ±0,15 m, pendiente de CAD; no constituye una precisión topográfica garantizada. | Arquitectura | ARQ-OF-20260710 · Arquitectura A101 / p. 3, A103 / p. 5, A106 / p. 8; A301Cuadro de materiales | 285.95 | Arquitectura | Fábrica de bloques · acabado mineral claro | block_masonry | [0.843137,0.823529,0.772549] | 0.96 | 0 | Bloque hueco documentado. Apariencia mineral clara para distinguir el cerramiento; no confirma un revoco ni su espesor. | Arquitectura; BIM · Arquitectura | El plano general de 2026-07-31 mantiene el edificio de oficinas de 200 m², mientras documentación anterior indica su supresión. Se conserva lo dibujado, pendiente de confirmación de la propiedad y del equipo de diseño.
Edificio de oficinas · Fábrica de bloques huecos de hormigón de 200 mm · eje B · tramo 43 | Planos de arquitectura del edificio de oficinas | Bloque hueco de hormigón de árido ligero | 1.9 × 0.2 × 1.1 | 285.95 | 287.05 | 0.418 | office_0165 | yes | 0.456924 | 1.90953 | 1.1 | 5.38 | 0.418001 | office | Edificio de oficinas | {"name":"Bloque hueco de hormigón de árido ligero","source":"ARQ-OF-20260710 · Arquitectura A101 / p. 3, A103 / p. 5, A106 / p. 8; A301Cuadro de materiales ","status":"known"} | {"documented":[{"label":"Espesor del muro","value":0.2,"unit":"m","source":"ARQ-OF-20260710 · Arquitectura A101 / p. 3, A103 / p. 5, A106 / p. 8; A301Cuadro de materiales ","status":"documentado"}],"geometry":[{"label":"Dimensiones de la caja local del elemento (X, Y, Z)","value":"1.9 × 0.2 × 1.1","unit":"m","source":"Malla triangulada del elemento en ejes locales del edificio","status":"derivado"},{"label":"Cota mínima absoluta de la malla","value":285.95,"unit":"m","source":"Malla de proyecto y origen altimétrico 285 m","status":"derivado"},{"label":"Cota máxima absoluta de la malla","value":287.05,"unit":"m","source":"Malla de proyecto y origen altimétrico 285 m","status":"derivado"},{"label":"Volumen geométrico bruto","value":0.418,"unit":"m³","source":"Malla cerrada del elemento","status":"derivado"}],"notes":["Las dimensiones documentadas proceden de anotaciones o cuadros; la caja y el volumen se calculan a partir de la malla.","El volumen es exclusivamente geométrico y bruto; no representa una medición neta de material ni una cantidad de compra."]} | {"documentId":"ARQ-OF-20260710","title":"Planos de arquitectura del edificio de oficinas","date":"2026-07-10","sheet":"Arquitectura A101 / p. 3, A103 / p. 5, A106 / p. 8; A301Cuadro de materiales "} | ["El plano general de 2026-07-31 mantiene el edificio de oficinas de 200 m², mientras documentación anterior indica su supresión. Se conserva lo dibujado, pendiente de confirmación de la propiedad y del equipo de diseño.","Envolvente exterior controlada por la planta de arquitectura; no se han modelado individualmente todas las capas de acabado.","Registro de líneas del PDF general, envolvente de 20 × 10 m; eje local 1 al norte y acceso del lado A al oeste. Estimación de trabajo de implantación de ±0,15 m, pendiente de CAD; no constituye una precisión topográfica garantizada."] | {"horizontalStatus":"derivado","verticalStatus":"derivado","baseElevationM":285.95,"note":"Registro de líneas del PDF general, envolvente de 20 × 10 m; eje local 1 al norte y acceso del lado A al oeste. Estimación de trabajo de implantación de ±0,15 m, pendiente de CAD; no constituye una precisión topográfica garantizada."} | {"Pset_WallCommon":{"IsExternal":{"value":true,"source":"ARQ-OF-20260710 · A101, A103 y alzados; elemento de la envolvente exterior identificada en planta","status":"known"}}} | {"boundingBoxM":{"min":[25.058424,75.605827,0.95],"max":[25.515348,77.515362,2.05]},"extentsM":[0.456924,1.909535,1.1],"meshSurfaceM2":5.380003,"meshVolumeM3":0.418001,"closedSolid":true,"basis":"Geometría triangulada releída del IFC; envolventes y magnitudes no contractuales."} | {"material":true,"document":true,"quantities":true,"containerGuid":"3ztlotcerHPueDgxP84R6z","containerName":"Planta baja"} | {"id":"architecture","name":"Arquitectura"} | {"profileId":"block_masonry","name":"Fábrica de bloques · acabado mineral claro","materialName":"Bloque hueco de hormigón de árido ligero","physicalMaterialStatus":"known","physicalMaterialSource":"ARQ-OF-20260710 · Arquitectura A101 / p. 3, A103 / p. 5, A106 / p. 8; A301Cuadro de materiales ","appearanceStatus":"criterio_visual","appearanceBasis":"Bloque hueco documentado. Apariencia mineral clara para distinguir el cerramiento; no confirma un revoco ni su espesor.","note":"La apariencia gráfica no modifica ni confirma la especificación física del material."} | {"elementId":"office_0165","ifcGuid":"3rHnCwQwDKRBFRDZCeftJK","ifcClass":"IfcWall","buildingId":"office","buildingName":"Edificio de oficinas","sourceDocumentId":"ARQ-OF-20260710","sourceRepresentationKind":"documentary_mesh"} | {"layerId":"architecture","layerName":"Arquitectura","role":"Muro","basis":"Clasificación por función del elemento; no modifica las especificaciones documentales."} | architecture | {"profileId":"block_masonry","name":"Fábrica de bloques · acabado mineral claro","status":"criterio_visual","basis":"Bloque hueco documentado. Apariencia mineral clara para distinguir el cerramiento; no confirma un revoco ni su espesor.","physicalMaterialUnchanged":true} | ARQ-OF-20260710 · Arquitectura A101 / p. 3, A103 / p. 5, A106 / p. 8; A301Cuadro de materiales | Dimensiones contrastadas con los planos; reconstrucción geométrica a partir de documentación de diseño. | 0.2 | Muros segmentados con huecos reales para puertas y ventanas. | Envolvente exterior controlada por la planta de arquitectura; no se han modelado individualmente todas las capas de acabado. | Registro de líneas del PDF general, envolvente de 20 × 10 m; eje local 1 al norte y acceso del lado A al oeste. Estimación de trabajo de implantación de ±0,15 m, pendiente de CAD; no constituye una precisión topográfica garantizada. | Arquitectura | ARQ-OF-20260710 · Arquitectura A101 / p. 3, A103 / p. 5, A106 / p. 8; A301Cuadro de materiales | 285.95 | Arquitectura | Fábrica de bloques · acabado mineral claro | block_masonry | [0.843137,0.823529,0.772549] | 0.96 | 0 | Bloque hueco documentado. Apariencia mineral clara para distinguir el cerramiento; no confirma un revoco ni su espesor. | Arquitectura; BIM · Arquitectura | El plano general de 2026-07-31 mantiene el edificio de oficinas de 200 m², mientras documentación anterior indica su supresión. Se conserva lo dibujado, pendiente de confirmación de la propiedad y del equipo de diseño.
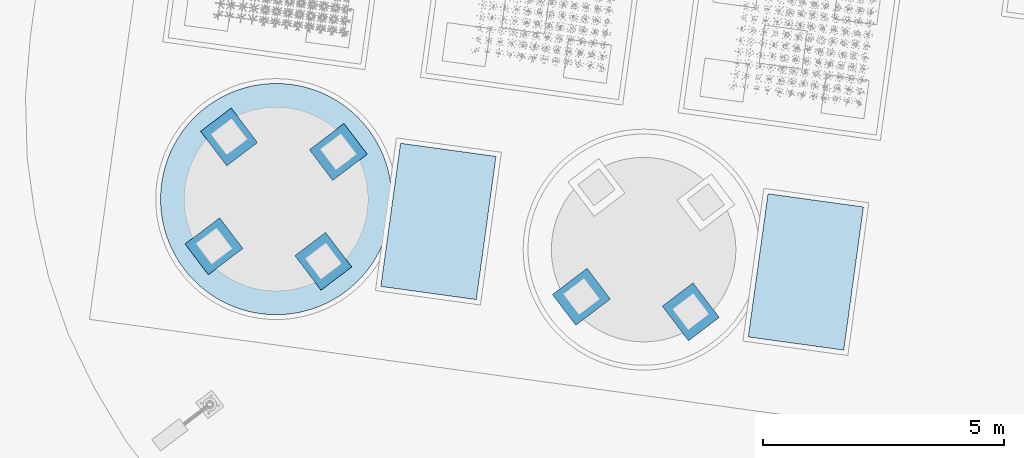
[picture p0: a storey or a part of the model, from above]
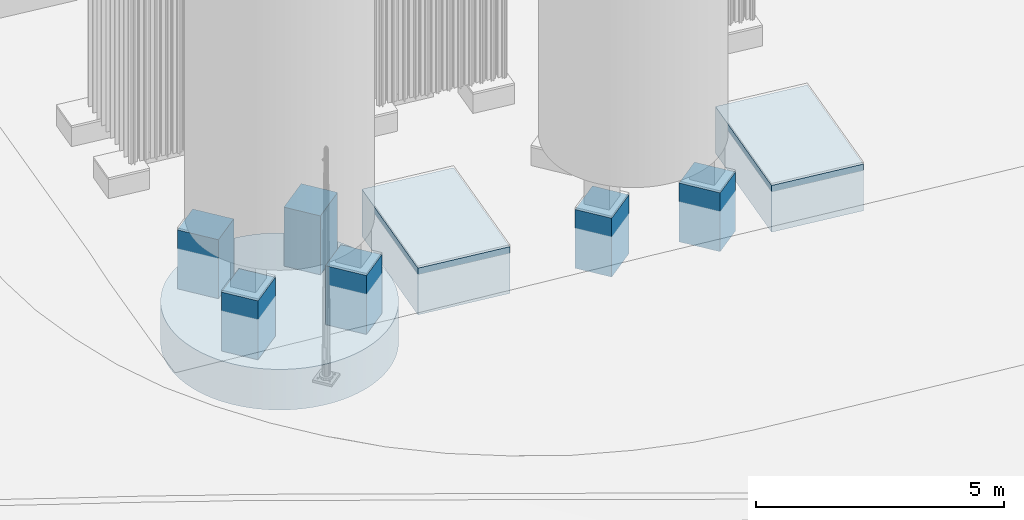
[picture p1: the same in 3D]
Properties of the parts of a building model (IFC4), part 127 of 134

# IfcWall (187)
Name | Document | Material = JH_Trazabilidad, Material = name | Dimensiones de la caja local del elemento (X, Y, Z) | Cota mínima absoluta de la malla (m) | Cota máxima absoluta de la malla (m) | Volumen geométrico bruto (m3) = Volumen geométrico (m³) | Reference = Identificador del elemento = Identificador | IsExternal | ExtensionX (m) | ExtensionY (m) | ExtensionZ (m) | SuperficieDeLaMalla (m2) | VolumenGeometrico (m3) = GrossVolume (m3) | buildingId | buildingName = Edificio | material | dimensions | JH_InformacionBIM, source = DocumentoFuente | issues = IncidenciasPendientes | positioning = PosicionYEstado | commonProperties | geometryMetrics | ifcAssociations | visualLayer | materialAppearance | visualizationIdentity | classification | layerId = IdentificadorCapa | appearance | Planos de referencia | Base geométrica | Espesor del muro (m) = Espesor del muro (m) | Tratamiento de los huecos | Representación de los acabados | Estado de la implantación | Disciplina | Referencia del material = JH_EvidenciaDeMaterial, source | Cota de planta baja terminada (m) | Capa BIM = NombreCapa | Acabado de visualización = Acabado | Perfil | ColorRGB | Rugosidad | Metallicidad | Referencia | Group | Discrepancia entre versiones
Edificio de oficinas · Fábrica de bloques huecos de hormigón de 200 mm · eje B · tramo 44 | Planos de arquitectura del edificio de oficinas | Bloque hueco de hormigón de árido ligero | 1.9 × 0.2 × 1.2 | 287.05 | 288.25 | 0.456 | office_0166 | yes | 0.456924 | 1.90953 | 1.2 | 5.8 | 0.456001 | office | Edificio de oficinas | {"name":"Bloque hueco de hormigón de árido ligero","source":"ARQ-OF-20260710 · Arquitectura A101 / p. 3, A103 / p. 5, A106 / p. 8; A301Cuadro de materiales ","status":"known"} | {"documented":[{"label":"Espesor del muro","value":0.2,"unit":"m","source":"ARQ-OF-20260710 · Arquitectura A101 / p. 3, A103 / p. 5, A106 / p. 8; A301Cuadro de materiales ","status":"documentado"}],"geometry":[{"label":"Dimensiones de la caja local del elemento (X, Y, Z)","value":"1.9 × 0.2 × 1.2","unit":"m","source":"Malla triangulada del elemento en ejes locales del edificio","status":"derivado"},{"label":"Cota mínima absoluta de la malla","value":287.05,"unit":"m","source":"Malla de proyecto y origen altimétrico 285 m","status":"derivado"},{"label":"Cota máxima absoluta de la malla","value":288.25,"unit":"m","source":"Malla de proyecto y origen altimétrico 285 m","status":"derivado"},{"label":"Volumen geométrico bruto","value":0.456,"unit":"m³","source":"Malla cerrada del elemento","status":"derivado"}],"notes":["Las dimensiones documentadas proceden de anotaciones o cuadros; la caja y el volumen se calculan a partir de la malla.","El volumen es exclusivamente geométrico y bruto; no representa una medición neta de material ni una cantidad de compra."]} | {"documentId":"ARQ-OF-20260710","title":"Planos de arquitectura del edificio de oficinas","date":"2026-07-10","sheet":"Arquitectura A101 / p. 3, A103 / p. 5, A106 / p. 8; A301Cuadro de materiales "} | ["El plano general de 2026-07-31 mantiene el edificio de oficinas de 200 m², mientras documentación anterior indica su supresión. Se conserva lo dibujado, pendiente de confirmación de la propiedad y del equipo de diseño.","Envolvente exterior controlada por la planta de arquitectura; no se han modelado individualmente todas las capas de acabado.","Registro de líneas del PDF general, envolvente de 20 × 10 m; eje local 1 al norte y acceso del lado A al oeste. Estimación de trabajo de implantación de ±0,15 m, pendiente de CAD; no constituye una precisión topográfica garantizada."] | {"horizontalStatus":"derivado","verticalStatus":"derivado","baseElevationM":285.95,"note":"Registro de líneas del PDF general, envolvente de 20 × 10 m; eje local 1 al norte y acceso del lado A al oeste. Estimación de trabajo de implantación de ±0,15 m, pendiente de CAD; no constituye una precisión topográfica garantizada."} | {"Pset_WallCommon":{"IsExternal":{"value":true,"source":"ARQ-OF-20260710 · A101, A103 y alzados; elemento de la envolvente exterior identificada en planta","status":"known"}}} | {"boundingBoxM":{"min":[25.058424,75.605827,2.05],"max":[25.515348,77.515362,3.25]},"extentsM":[0.456924,1.909535,1.2],"meshSurfaceM2":5.800003,"meshVolumeM3":0.456001,"closedSolid":true,"basis":"Geometría triangulada releída del IFC; envolventes y magnitudes no contractuales."} | {"material":true,"document":true,"quantities":true,"containerGuid":"3ztlotcerHPueDgxP84R6z","containerName":"Planta baja"} | {"id":"architecture","name":"Arquitectura"} | {"profileId":"block_masonry","name":"Fábrica de bloques · acabado mineral claro","materialName":"Bloque hueco de hormigón de árido ligero","physicalMaterialStatus":"known","physicalMaterialSource":"ARQ-OF-20260710 · Arquitectura A101 / p. 3, A103 / p. 5, A106 / p. 8; A301Cuadro de materiales ","appearanceStatus":"criterio_visual","appearanceBasis":"Bloque hueco documentado. Apariencia mineral clara para distinguir el cerramiento; no confirma un revoco ni su espesor.","note":"La apariencia gráfica no modifica ni confirma la especificación física del material."} | {"elementId":"office_0166","ifcGuid":"1fwLvV5EPP6xpQUaZZqvHy","ifcClass":"IfcWall","buildingId":"office","buildingName":"Edificio de oficinas","sourceDocumentId":"ARQ-OF-20260710","sourceRepresentationKind":"documentary_mesh"} | {"layerId":"architecture","layerName":"Arquitectura","role":"Muro","basis":"Clasificación por función del elemento; no modifica las especificaciones documentales."} | architecture | {"profileId":"block_masonry","name":"Fábrica de bloques · acabado mineral claro","status":"criterio_visual","basis":"Bloque hueco documentado. Apariencia mineral clara para distinguir el cerramiento; no confirma un revoco ni su espesor.","physicalMaterialUnchanged":true} | ARQ-OF-20260710 · Arquitectura A101 / p. 3, A103 / p. 5, A106 / p. 8; A301Cuadro de materiales | Dimensiones contrastadas con los planos; reconstrucción geométrica a partir de documentación de diseño. | 0.2 | Muros segmentados con huecos reales para puertas y ventanas. | Envolvente exterior controlada por la planta de arquitectura; no se han modelado individualmente todas las capas de acabado. | Registro de líneas del PDF general, envolvente de 20 × 10 m; eje local 1 al norte y acceso del lado A al oeste. Estimación de trabajo de implantación de ±0,15 m, pendiente de CAD; no constituye una precisión topográfica garantizada. | Arquitectura | ARQ-OF-20260710 · Arquitectura A101 / p. 3, A103 / p. 5, A106 / p. 8; A301Cuadro de materiales | 285.95 | Arquitectura | Fábrica de bloques · acabado mineral claro | block_masonry | [0.843137,0.823529,0.772549] | 0.96 | 0 | Bloque hueco documentado. Apariencia mineral clara para distinguir el cerramiento; no confirma un revoco ni su espesor. | Arquitectura; BIM · Arquitectura | El plano general de 2026-07-31 mantiene el edificio de oficinas de 200 m², mientras documentación anterior indica su supresión. Se conserva lo dibujado, pendiente de confirmación de la propiedad y del equipo de diseño.
Edificio de oficinas · Fábrica de bloques huecos de hormigón de 200 mm · eje B · tramo 45 | Planos de arquitectura del edificio de oficinas | Bloque hueco de hormigón de árido ligero | 1.9 × 0.2 × 1.1 | 288.25 | 289.35 | 0.418 | office_0167 | yes | 0.456924 | 1.90953 | 1.1 | 5.38 | 0.418001 | office | Edificio de oficinas | {"name":"Bloque hueco de hormigón de árido ligero","source":"ARQ-OF-20260710 · Arquitectura A101 / p. 3, A103 / p. 5, A106 / p. 8; A301Cuadro de materiales ","status":"known"} | {"documented":[{"label":"Espesor del muro","value":0.2,"unit":"m","source":"ARQ-OF-20260710 · Arquitectura A101 / p. 3, A103 / p. 5, A106 / p. 8; A301Cuadro de materiales ","status":"documentado"}],"geometry":[{"label":"Dimensiones de la caja local del elemento (X, Y, Z)","value":"1.9 × 0.2 × 1.1","unit":"m","source":"Malla triangulada del elemento en ejes locales del edificio","status":"derivado"},{"label":"Cota mínima absoluta de la malla","value":288.25,"unit":"m","source":"Malla de proyecto y origen altimétrico 285 m","status":"derivado"},{"label":"Cota máxima absoluta de la malla","value":289.35,"unit":"m","source":"Malla de proyecto y origen altimétrico 285 m","status":"derivado"},{"label":"Volumen geométrico bruto","value":0.418,"unit":"m³","source":"Malla cerrada del elemento","status":"derivado"}],"notes":["Las dimensiones documentadas proceden de anotaciones o cuadros; la caja y el volumen se calculan a partir de la malla.","El volumen es exclusivamente geométrico y bruto; no representa una medición neta de material ni una cantidad de compra."]} | {"documentId":"ARQ-OF-20260710","title":"Planos de arquitectura del edificio de oficinas","date":"2026-07-10","sheet":"Arquitectura A101 / p. 3, A103 / p. 5, A106 / p. 8; A301Cuadro de materiales "} | ["El plano general de 2026-07-31 mantiene el edificio de oficinas de 200 m², mientras documentación anterior indica su supresión. Se conserva lo dibujado, pendiente de confirmación de la propiedad y del equipo de diseño.","Envolvente exterior controlada por la planta de arquitectura; no se han modelado individualmente todas las capas de acabado.","Registro de líneas del PDF general, envolvente de 20 × 10 m; eje local 1 al norte y acceso del lado A al oeste. Estimación de trabajo de implantación de ±0,15 m, pendiente de CAD; no constituye una precisión topográfica garantizada."] | {"horizontalStatus":"derivado","verticalStatus":"derivado","baseElevationM":285.95,"note":"Registro de líneas del PDF general, envolvente de 20 × 10 m; eje local 1 al norte y acceso del lado A al oeste. Estimación de trabajo de implantación de ±0,15 m, pendiente de CAD; no constituye una precisión topográfica garantizada."} | {"Pset_WallCommon":{"IsExternal":{"value":true,"source":"ARQ-OF-20260710 · A101, A103 y alzados; elemento de la envolvente exterior identificada en planta","status":"known"}}} | {"boundingBoxM":{"min":[25.058424,75.605827,3.25],"max":[25.515348,77.515362,4.35]},"extentsM":[0.456924,1.909535,1.1],"meshSurfaceM2":5.380003,"meshVolumeM3":0.418001,"closedSolid":true,"basis":"Geometría triangulada releída del IFC; envolventes y magnitudes no contractuales."} | {"material":true,"document":true,"quantities":true,"containerGuid":"3ztlotcerHPueDgxP84R6z","containerName":"Planta baja"} | {"id":"architecture","name":"Arquitectura"} | {"profileId":"block_masonry","name":"Fábrica de bloques · acabado mineral claro","materialName":"Bloque hueco de hormigón de árido ligero","physicalMaterialStatus":"known","physicalMaterialSource":"ARQ-OF-20260710 · Arquitectura A101 / p. 3, A103 / p. 5, A106 / p. 8; A301Cuadro de materiales ","appearanceStatus":"criterio_visual","appearanceBasis":"Bloque hueco documentado. Apariencia mineral clara para distinguir el cerramiento; no confirma un revoco ni su espesor.","note":"La apariencia gráfica no modifica ni confirma la especificación física del material."} | {"elementId":"office_0167","ifcGuid":"04aGz4KCXHmvesIXB1snhJ","ifcClass":"IfcWall","buildingId":"office","buildingName":"Edificio de oficinas","sourceDocumentId":"ARQ-OF-20260710","sourceRepresentationKind":"documentary_mesh"} | {"layerId":"architecture","layerName":"Arquitectura","role":"Muro","basis":"Clasificación por función del elemento; no modifica las especificaciones documentales."} | architecture | {"profileId":"block_masonry","name":"Fábrica de bloques · acabado mineral claro","status":"criterio_visual","basis":"Bloque hueco documentado. Apariencia mineral clara para distinguir el cerramiento; no confirma un revoco ni su espesor.","physicalMaterialUnchanged":true} | ARQ-OF-20260710 · Arquitectura A101 / p. 3, A103 / p. 5, A106 / p. 8; A301Cuadro de materiales | Dimensiones contrastadas con los planos; reconstrucción geométrica a partir de documentación de diseño. | 0.2 | Muros segmentados con huecos reales para puertas y ventanas. | Envolvente exterior controlada por la planta de arquitectura; no se han modelado individualmente todas las capas de acabado. | Registro de líneas del PDF general, envolvente de 20 × 10 m; eje local 1 al norte y acceso del lado A al oeste. Estimación de trabajo de implantación de ±0,15 m, pendiente de CAD; no constituye una precisión topográfica garantizada. | Arquitectura | ARQ-OF-20260710 · Arquitectura A101 / p. 3, A103 / p. 5, A106 / p. 8; A301Cuadro de materiales | 285.95 | Arquitectura | Fábrica de bloques · acabado mineral claro | block_masonry | [0.843137,0.823529,0.772549] | 0.96 | 0 | Bloque hueco documentado. Apariencia mineral clara para distinguir el cerramiento; no confirma un revoco ni su espesor. | Arquitectura; BIM · Arquitectura | El plano general de 2026-07-31 mantiene el edificio de oficinas de 200 m², mientras documentación anterior indica su supresión. Se conserva lo dibujado, pendiente de confirmación de la propiedad y del equipo de diseño.
Edificio de oficinas · Fábrica de bloques huecos de hormigón de 200 mm · eje B · tramo 46 | Planos de arquitectura del edificio de oficinas | Bloque hueco de hormigón de árido ligero | 1.9 × 0.2 × 1.6 | 289.35 | 290.95 | 0.608 | office_0168 | yes | 0.456924 | 1.90953 | 1.6 | 7.48 | 0.608001 | office | Edificio de oficinas | {"name":"Bloque hueco de hormigón de árido ligero","source":"ARQ-OF-20260710 · Arquitectura A101 / p. 3, A103 / p. 5, A106 / p. 8; A301Cuadro de materiales ","status":"known"} | {"documented":[{"label":"Espesor del muro","value":0.2,"unit":"m","source":"ARQ-OF-20260710 · Arquitectura A101 / p. 3, A103 / p. 5, A106 / p. 8; A301Cuadro de materiales ","status":"documentado"}],"geometry":[{"label":"Dimensiones de la caja local del elemento (X, Y, Z)","value":"1.9 × 0.2 × 1.6","unit":"m","source":"Malla triangulada del elemento en ejes locales del edificio","status":"derivado"},{"label":"Cota mínima absoluta de la malla","value":289.35,"unit":"m","source":"Malla de proyecto y origen altimétrico 285 m","status":"derivado"},{"label":"Cota máxima absoluta de la malla","value":290.95,"unit":"m","source":"Malla de proyecto y origen altimétrico 285 m","status":"derivado"},{"label":"Volumen geométrico bruto","value":0.608,"unit":"m³","source":"Malla cerrada del elemento","status":"derivado"}],"notes":["Las dimensiones documentadas proceden de anotaciones o cuadros; la caja y el volumen se calculan a partir de la malla.","El volumen es exclusivamente geométrico y bruto; no representa una medición neta de material ni una cantidad de compra."]} | {"documentId":"ARQ-OF-20260710","title":"Planos de arquitectura del edificio de oficinas","date":"2026-07-10","sheet":"Arquitectura A101 / p. 3, A103 / p. 5, A106 / p. 8; A301Cuadro de materiales "} | ["El plano general de 2026-07-31 mantiene el edificio de oficinas de 200 m², mientras documentación anterior indica su supresión. Se conserva lo dibujado, pendiente de confirmación de la propiedad y del equipo de diseño.","Envolvente exterior controlada por la planta de arquitectura; no se han modelado individualmente todas las capas de acabado.","Registro de líneas del PDF general, envolvente de 20 × 10 m; eje local 1 al norte y acceso del lado A al oeste. Estimación de trabajo de implantación de ±0,15 m, pendiente de CAD; no constituye una precisión topográfica garantizada."] | {"horizontalStatus":"derivado","verticalStatus":"derivado","baseElevationM":285.95,"note":"Registro de líneas del PDF general, envolvente de 20 × 10 m; eje local 1 al norte y acceso del lado A al oeste. Estimación de trabajo de implantación de ±0,15 m, pendiente de CAD; no constituye una precisión topográfica garantizada."} | {"Pset_WallCommon":{"IsExternal":{"value":true,"source":"ARQ-OF-20260710 · A101, A103 y alzados; elemento de la envolvente exterior identificada en planta","status":"known"}}} | {"boundingBoxM":{"min":[25.058424,75.605827,4.35],"max":[25.515348,77.515362,5.95]},"extentsM":[0.456924,1.909535,1.6],"meshSurfaceM2":7.480004,"meshVolumeM3":0.608001,"closedSolid":true,"basis":"Geometría triangulada releída del IFC; envolventes y magnitudes no contractuales."} | {"material":true,"document":true,"quantities":true,"containerGuid":"3ztlotcerHPueDgxP84R6z","containerName":"Planta baja"} | {"id":"architecture","name":"Arquitectura"} | {"profileId":"block_masonry","name":"Fábrica de bloques · acabado mineral claro","materialName":"Bloque hueco de hormigón de árido ligero","physicalMaterialStatus":"known","physicalMaterialSource":"ARQ-OF-20260710 · Arquitectura A101 / p. 3, A103 / p. 5, A106 / p. 8; A301Cuadro de materiales ","appearanceStatus":"criterio_visual","appearanceBasis":"Bloque hueco documentado. Apariencia mineral clara para distinguir el cerramiento; no confirma un revoco ni su espesor.","note":"La apariencia gráfica no modifica ni confirma la especificación física del material."} | {"elementId":"office_0168","ifcGuid":"2Wrioo$d1N0wn09gRTnzBe","ifcClass":"IfcWall","buildingId":"office","buildingName":"Edificio de oficinas","sourceDocumentId":"ARQ-OF-20260710","sourceRepresentationKind":"documentary_mesh"} | {"layerId":"architecture","layerName":"Arquitectura","role":"Muro","basis":"Clasificación por función del elemento; no modifica las especificaciones documentales."} | architecture | {"profileId":"block_masonry","name":"Fábrica de bloques · acabado mineral claro","status":"criterio_visual","basis":"Bloque hueco documentado. Apariencia mineral clara para distinguir el cerramiento; no confirma un revoco ni su espesor.","physicalMaterialUnchanged":true} | ARQ-OF-20260710 · Arquitectura A101 / p. 3, A103 / p. 5, A106 / p. 8; A301Cuadro de materiales | Dimensiones contrastadas con los planos; reconstrucción geométrica a partir de documentación de diseño. | 0.2 | Muros segmentados con huecos reales para puertas y ventanas. | Envolvente exterior controlada por la planta de arquitectura; no se han modelado individualmente todas las capas de acabado. | Registro de líneas del PDF general, envolvente de 20 × 10 m; eje local 1 al norte y acceso del lado A al oeste. Estimación de trabajo de implantación de ±0,15 m, pendiente de CAD; no constituye una precisión topográfica garantizada. | Arquitectura | ARQ-OF-20260710 · Arquitectura A101 / p. 3, A103 / p. 5, A106 / p. 8; A301Cuadro de materiales | 285.95 | Arquitectura | Fábrica de bloques · acabado mineral claro | block_masonry | [0.843137,0.823529,0.772549] | 0.96 | 0 | Bloque hueco documentado. Apariencia mineral clara para distinguir el cerramiento; no confirma un revoco ni su espesor. | Arquitectura; BIM · Arquitectura | El plano general de 2026-07-31 mantiene el edificio de oficinas de 200 m², mientras documentación anterior indica su supresión. Se conserva lo dibujado, pendiente de confirmación de la propiedad y del equipo de diseño.
Edificio de oficinas · Fábrica de bloques huecos de hormigón de 200 mm · eje B · tramo 47 | Planos de arquitectura del edificio de oficinas | Bloque hueco de hormigón de árido ligero | 0.6 × 0.2 × 1.1 | 285.95 | 287.05 | 0.132 | office_0169 | yes | 0.279858 | 0.621649 | 1.1 | 2 | 0.132 | office | Edificio de oficinas | {"name":"Bloque hueco de hormigón de árido ligero","source":"ARQ-OF-20260710 · Arquitectura A101 / p. 3, A103 / p. 5, A106 / p. 8; A301Cuadro de materiales ","status":"known"} | {"documented":[{"label":"Espesor del muro","value":0.2,"unit":"m","source":"ARQ-OF-20260710 · Arquitectura A101 / p. 3, A103 / p. 5, A106 / p. 8; A301Cuadro de materiales ","status":"documentado"}],"geometry":[{"label":"Dimensiones de la caja local del elemento (X, Y, Z)","value":"0.6 × 0.2 × 1.1","unit":"m","source":"Malla triangulada del elemento en ejes locales del edificio","status":"derivado"},{"label":"Cota mínima absoluta de la malla","value":285.95,"unit":"m","source":"Malla de proyecto y origen altimétrico 285 m","status":"derivado"},{"label":"Cota máxima absoluta de la malla","value":287.05,"unit":"m","source":"Malla de proyecto y origen altimétrico 285 m","status":"derivado"},{"label":"Volumen geométrico bruto","value":0.132,"unit":"m³","source":"Malla cerrada del elemento","status":"derivado"}],"notes":["Las dimensiones documentadas proceden de anotaciones o cuadros; la caja y el volumen se calculan a partir de la malla.","El volumen es exclusivamente geométrico y bruto; no representa una medición neta de material ni una cantidad de compra."]} | {"documentId":"ARQ-OF-20260710","title":"Planos de arquitectura del edificio de oficinas","date":"2026-07-10","sheet":"Arquitectura A101 / p. 3, A103 / p. 5, A106 / p. 8; A301Cuadro de materiales "} | ["El plano general de 2026-07-31 mantiene el edificio de oficinas de 200 m², mientras documentación anterior indica su supresión. Se conserva lo dibujado, pendiente de confirmación de la propiedad y del equipo de diseño.","Envolvente exterior controlada por la planta de arquitectura; no se han modelado individualmente todas las capas de acabado.","Registro de líneas del PDF general, envolvente de 20 × 10 m; eje local 1 al norte y acceso del lado A al oeste. Estimación de trabajo de implantación de ±0,15 m, pendiente de CAD; no constituye una precisión topográfica garantizada."] | {"horizontalStatus":"derivado","verticalStatus":"derivado","baseElevationM":285.95,"note":"Registro de líneas del PDF general, envolvente de 20 × 10 m; eje local 1 al norte y acceso del lado A al oeste. Estimación de trabajo de implantación de ±0,15 m, pendiente de CAD; no constituye una precisión topográfica garantizada."} | {"Pset_WallCommon":{"IsExternal":{"value":true,"source":"ARQ-OF-20260710 · A101, A103 y alzados; elemento de la envolvente exterior identificada en planta","status":"known"}}} | {"boundingBoxM":{"min":[24.976702,75.011419,0.95],"max":[25.25656,75.633068,2.05]},"extentsM":[0.279858,0.621649,1.1],"meshSurfaceM2":1.999998,"meshVolumeM3":0.132,"closedSolid":true,"basis":"Geometría triangulada releída del IFC; envolventes y magnitudes no contractuales."} | {"material":true,"document":true,"quantities":true,"containerGuid":"3ztlotcerHPueDgxP84R6z","containerName":"Planta baja"} | {"id":"architecture","name":"Arquitectura"} | {"profileId":"block_masonry","name":"Fábrica de bloques · acabado mineral claro","materialName":"Bloque hueco de hormigón de árido ligero","physicalMaterialStatus":"known","physicalMaterialSource":"ARQ-OF-20260710 · Arquitectura A101 / p. 3, A103 / p. 5, A106 / p. 8; A301Cuadro de materiales ","appearanceStatus":"criterio_visual","appearanceBasis":"Bloque hueco documentado. Apariencia mineral clara para distinguir el cerramiento; no confirma un revoco ni su espesor.","note":"La apariencia gráfica no modifica ni confirma la especificación física del material."} | {"elementId":"office_0169","ifcGuid":"1DCR2mYPzO5fdPTV2nbNi2","ifcClass":"IfcWall","buildingId":"office","buildingName":"Edificio de oficinas","sourceDocumentId":"ARQ-OF-20260710","sourceRepresentationKind":"documentary_mesh"} | {"layerId":"architecture","layerName":"Arquitectura","role":"Muro","basis":"Clasificación por función del elemento; no modifica las especificaciones documentales."} | architecture | {"profileId":"block_masonry","name":"Fábrica de bloques · acabado mineral claro","status":"criterio_visual","basis":"Bloque hueco documentado. Apariencia mineral clara para distinguir el cerramiento; no confirma un revoco ni su espesor.","physicalMaterialUnchanged":true} | ARQ-OF-20260710 · Arquitectura A101 / p. 3, A103 / p. 5, A106 / p. 8; A301Cuadro de materiales | Dimensiones contrastadas con los planos; reconstrucción geométrica a partir de documentación de diseño. | 0.2 | Muros segmentados con huecos reales para puertas y ventanas. | Envolvente exterior controlada por la planta de arquitectura; no se han modelado individualmente todas las capas de acabado. | Registro de líneas del PDF general, envolvente de 20 × 10 m; eje local 1 al norte y acceso del lado A al oeste. Estimación de trabajo de implantación de ±0,15 m, pendiente de CAD; no constituye una precisión topográfica garantizada. | Arquitectura | ARQ-OF-20260710 · Arquitectura A101 / p. 3, A103 / p. 5, A106 / p. 8; A301Cuadro de materiales | 285.95 | Arquitectura | Fábrica de bloques · acabado mineral claro | block_masonry | [0.843137,0.823529,0.772549] | 0.96 | 0 | Bloque hueco documentado. Apariencia mineral clara para distinguir el cerramiento; no confirma un revoco ni su espesor. | Arquitectura; BIM · Arquitectura | El plano general de 2026-07-31 mantiene el edificio de oficinas de 200 m², mientras documentación anterior indica su supresión. Se conserva lo dibujado, pendiente de confirmación de la propiedad y del equipo de diseño.
Edificio de oficinas · Fábrica de bloques huecos de hormigón de 200 mm · eje B · tramo 48 | Planos de arquitectura del edificio de oficinas | Bloque hueco de hormigón de árido ligero | 0.6 × 0.2 × 1.6 | 289.35 | 290.95 | 0.192 | office_0170 | yes | 0.279858 | 0.621649 | 1.6 | 2.8 | 0.192 | office | Edificio de oficinas | {"name":"Bloque hueco de hormigón de árido ligero","source":"ARQ-OF-20260710 · Arquitectura A101 / p. 3, A103 / p. 5, A106 / p. 8; A301Cuadro de materiales ","status":"known"} | {"documented":[{"label":"Espesor del muro","value":0.2,"unit":"m","source":"ARQ-OF-20260710 · Arquitectura A101 / p. 3, A103 / p. 5, A106 / p. 8; A301Cuadro de materiales ","status":"documentado"}],"geometry":[{"label":"Dimensiones de la caja local del elemento (X, Y, Z)","value":"0.6 × 0.2 × 1.6","unit":"m","source":"Malla triangulada del elemento en ejes locales del edificio","status":"derivado"},{"label":"Cota mínima absoluta de la malla","value":289.35,"unit":"m","source":"Malla de proyecto y origen altimétrico 285 m","status":"derivado"},{"label":"Cota máxima absoluta de la malla","value":290.95,"unit":"m","source":"Malla de proyecto y origen altimétrico 285 m","status":"derivado"},{"label":"Volumen geométrico bruto","value":0.192,"unit":"m³","source":"Malla cerrada del elemento","status":"derivado"}],"notes":["Las dimensiones documentadas proceden de anotaciones o cuadros; la caja y el volumen se calculan a partir de la malla.","El volumen es exclusivamente geométrico y bruto; no representa una medición neta de material ni una cantidad de compra."]} | {"documentId":"ARQ-OF-20260710","title":"Planos de arquitectura del edificio de oficinas","date":"2026-07-10","sheet":"Arquitectura A101 / p. 3, A103 / p. 5, A106 / p. 8; A301Cuadro de materiales "} | ["El plano general de 2026-07-31 mantiene el edificio de oficinas de 200 m², mientras documentación anterior indica su supresión. Se conserva lo dibujado, pendiente de confirmación de la propiedad y del equipo de diseño.","Envolvente exterior controlada por la planta de arquitectura; no se han modelado individualmente todas las capas de acabado.","Registro de líneas del PDF general, envolvente de 20 × 10 m; eje local 1 al norte y acceso del lado A al oeste. Estimación de trabajo de implantación de ±0,15 m, pendiente de CAD; no constituye una precisión topográfica garantizada."] | {"horizontalStatus":"derivado","verticalStatus":"derivado","baseElevationM":285.95,"note":"Registro de líneas del PDF general, envolvente de 20 × 10 m; eje local 1 al norte y acceso del lado A al oeste. Estimación de trabajo de implantación de ±0,15 m, pendiente de CAD; no constituye una precisión topográfica garantizada."} | {"Pset_WallCommon":{"IsExternal":{"value":true,"source":"ARQ-OF-20260710 · A101, A103 y alzados; elemento de la envolvente exterior identificada en planta","status":"known"}}} | {"boundingBoxM":{"min":[24.976702,75.011419,4.35],"max":[25.25656,75.633068,5.95]},"extentsM":[0.279858,0.621649,1.6],"meshSurfaceM2":2.799997,"meshVolumeM3":0.192,"closedSolid":true,"basis":"Geometría triangulada releída del IFC; envolventes y magnitudes no contractuales."} | {"material":true,"document":true,"quantities":true,"containerGuid":"3ztlotcerHPueDgxP84R6z","containerName":"Planta baja"} | {"id":"architecture","name":"Arquitectura"} | {"profileId":"block_masonry","name":"Fábrica de bloques · acabado mineral claro","materialName":"Bloque hueco de hormigón de árido ligero","physicalMaterialStatus":"known","physicalMaterialSource":"ARQ-OF-20260710 · Arquitectura A101 / p. 3, A103 / p. 5, A106 / p. 8; A301Cuadro de materiales ","appearanceStatus":"criterio_visual","appearanceBasis":"Bloque hueco documentado. Apariencia mineral clara para distinguir el cerramiento; no confirma un revoco ni su espesor.","note":"La apariencia gráfica no modifica ni confirma la especificación física del material."} | {"elementId":"office_0170","ifcGuid":"0KrzF6xbnLNwEF6VXXMYrH","ifcClass":"IfcWall","buildingId":"office","buildingName":"Edificio de oficinas","sourceDocumentId":"ARQ-OF-20260710","sourceRepresentationKind":"documentary_mesh"} | {"layerId":"architecture","layerName":"Arquitectura","role":"Muro","basis":"Clasificación por función del elemento; no modifica las especificaciones documentales."} | architecture | {"profileId":"block_masonry","name":"Fábrica de bloques · acabado mineral claro","status":"criterio_visual","basis":"Bloque hueco documentado. Apariencia mineral clara para distinguir el cerramiento; no confirma un revoco ni su espesor.","physicalMaterialUnchanged":true} | ARQ-OF-20260710 · Arquitectura A101 / p. 3, A103 / p. 5, A106 / p. 8; A301Cuadro de materiales | Dimensiones contrastadas con los planos; reconstrucción geométrica a partir de documentación de diseño. | 0.2 | Muros segmentados con huecos reales para puertas y ventanas. | Envolvente exterior controlada por la planta de arquitectura; no se han modelado individualmente todas las capas de acabado. | Registro de líneas del PDF general, envolvente de 20 × 10 m; eje local 1 al norte y acceso del lado A al oeste. Estimación de trabajo de implantación de ±0,15 m, pendiente de CAD; no constituye una precisión topográfica garantizada. | Arquitectura | ARQ-OF-20260710 · Arquitectura A101 / p. 3, A103 / p. 5, A106 / p. 8; A301Cuadro de materiales | 285.95 | Arquitectura | Fábrica de bloques · acabado mineral claro | block_masonry | [0.843137,0.823529,0.772549] | 0.96 | 0 | Bloque hueco documentado. Apariencia mineral clara para distinguir el cerramiento; no confirma un revoco ni su espesor. | Arquitectura; BIM · Arquitectura | El plano general de 2026-07-31 mantiene el edificio de oficinas de 200 m², mientras documentación anterior indica su supresión. Se conserva lo dibujado, pendiente de confirmación de la propiedad y del equipo de diseño.
Edificio de oficinas · Fábrica de bloques huecos de hormigón de 200 mm · eje B · tramo 49 | Planos de arquitectura del edificio de oficinas | Bloque hueco de hormigón de árido ligero | 1.9 × 0.2 × 1.1 | 285.95 | 287.05 | 0.418 | office_0171 | yes | 0.456924 | 1.90953 | 1.1 | 5.38 | 0.418 | office | Edificio de oficinas | {"name":"Bloque hueco de hormigón de árido ligero","source":"ARQ-OF-20260710 · Arquitectura A101 / p. 3, A103 / p. 5, A106 / p. 8; A301Cuadro de materiales ","status":"known"} | {"documented":[{"label":"Espesor del muro","value":0.2,"unit":"m","source":"ARQ-OF-20260710 · Arquitectura A101 / p. 3, A103 / p. 5, A106 / p. 8; A301Cuadro de materiales ","status":"documentado"}],"geometry":[{"label":"Dimensiones de la caja local del elemento (X, Y, Z)","value":"1.9 × 0.2 × 1.1","unit":"m","source":"Malla triangulada del elemento en ejes locales del edificio","status":"derivado"},{"label":"Cota mínima absoluta de la malla","value":285.95,"unit":"m","source":"Malla de proyecto y origen altimétrico 285 m","status":"derivado"},{"label":"Cota máxima absoluta de la malla","value":287.05,"unit":"m","source":"Malla de proyecto y origen altimétrico 285 m","status":"derivado"},{"label":"Volumen geométrico bruto","value":0.418,"unit":"m³","source":"Malla cerrada del elemento","status":"derivado"}],"notes":["Las dimensiones documentadas proceden de anotaciones o cuadros; la caja y el volumen se calculan a partir de la malla.","El volumen es exclusivamente geométrico y bruto; no representa una medición neta de material ni una cantidad de compra."]} | {"documentId":"ARQ-OF-20260710","title":"Planos de arquitectura del edificio de oficinas","date":"2026-07-10","sheet":"Arquitectura A101 / p. 3, A103 / p. 5, A106 / p. 8; A301Cuadro de materiales "} | ["El plano general de 2026-07-31 mantiene el edificio de oficinas de 200 m², mientras documentación anterior indica su supresión. Se conserva lo dibujado, pendiente de confirmación de la propiedad y del equipo de diseño.","Envolvente exterior controlada por la planta de arquitectura; no se han modelado individualmente todas las capas de acabado.","Registro de líneas del PDF general, envolvente de 20 × 10 m; eje local 1 al norte y acceso del lado A al oeste. Estimación de trabajo de implantación de ±0,15 m, pendiente de CAD; no constituye una precisión topográfica garantizada."] | {"horizontalStatus":"derivado","verticalStatus":"derivado","baseElevationM":285.95,"note":"Registro de líneas del PDF general, envolvente de 20 × 10 m; eje local 1 al norte y acceso del lado A al oeste. Estimación de trabajo de implantación de ±0,15 m, pendiente de CAD; no constituye una precisión topográfica garantizada."} | {"Pset_WallCommon":{"IsExternal":{"value":true,"source":"ARQ-OF-20260710 · A101, A103 y alzados; elemento de la envolvente exterior identificada en planta","status":"known"}}} | {"boundingBoxM":{"min":[24.717914,73.129125,0.95],"max":[25.174838,75.03866,2.05]},"extentsM":[0.456924,1.909535,1.1],"meshSurfaceM2":5.380001,"meshVolumeM3":0.418,"closedSolid":true,"basis":"Geometría triangulada releída del IFC; envolventes y magnitudes no contractuales."} | {"material":true,"document":true,"quantities":true,"containerGuid":"3ztlotcerHPueDgxP84R6z","containerName":"Planta baja"} | {"id":"architecture","name":"Arquitectura"} | {"profileId":"block_masonry","name":"Fábrica de bloques · acabado mineral claro","materialName":"Bloque hueco de hormigón de árido ligero","physicalMaterialStatus":"known","physicalMaterialSource":"ARQ-OF-20260710 · Arquitectura A101 / p. 3, A103 / p. 5, A106 / p. 8; A301Cuadro de materiales ","appearanceStatus":"criterio_visual","appearanceBasis":"Bloque hueco documentado. Apariencia mineral clara para distinguir el cerramiento; no confirma un revoco ni su espesor.","note":"La apariencia gráfica no modifica ni confirma la especificación física del material."} | {"elementId":"office_0171","ifcGuid":"1YpqEDoETQYRih9xp5Jpt_","ifcClass":"IfcWall","buildingId":"office","buildingName":"Edificio de oficinas","sourceDocumentId":"ARQ-OF-20260710","sourceRepresentationKind":"documentary_mesh"} | {"layerId":"architecture","layerName":"Arquitectura","role":"Muro","basis":"Clasificación por función del elemento; no modifica las especificaciones documentales."} | architecture | {"profileId":"block_masonry","name":"Fábrica de bloques · acabado mineral claro","status":"criterio_visual","basis":"Bloque hueco documentado. Apariencia mineral clara para distinguir el cerramiento; no confirma un revoco ni su espesor.","physicalMaterialUnchanged":true} | ARQ-OF-20260710 · Arquitectura A101 / p. 3, A103 / p. 5, A106 / p. 8; A301Cuadro de materiales | Dimensiones contrastadas con los planos; reconstrucción geométrica a partir de documentación de diseño. | 0.2 | Muros segmentados con huecos reales para puertas y ventanas. | Envolvente exterior controlada por la planta de arquitectura; no se han modelado individualmente todas las capas de acabado. | Registro de líneas del PDF general, envolvente de 20 × 10 m; eje local 1 al norte y acceso del lado A al oeste. Estimación de trabajo de implantación de ±0,15 m, pendiente de CAD; no constituye una precisión topográfica garantizada. | Arquitectura | ARQ-OF-20260710 · Arquitectura A101 / p. 3, A103 / p. 5, A106 / p. 8; A301Cuadro de materiales | 285.95 | Arquitectura | Fábrica de bloques · acabado mineral claro | block_masonry | [0.843137,0.823529,0.772549] | 0.96 | 0 | Bloque hueco documentado. Apariencia mineral clara para distinguir el cerramiento; no confirma un revoco ni su espesor. | Arquitectura; BIM · Arquitectura | El plano general de 2026-07-31 mantiene el edificio de oficinas de 200 m², mientras documentación anterior indica su supresión. Se conserva lo dibujado, pendiente de confirmación de la propiedad y del equipo de diseño.
Edificio de oficinas · Fábrica de bloques huecos de hormigón de 200 mm · eje B · tramo 50 | Planos de arquitectura del edificio de oficinas | Bloque hueco de hormigón de árido ligero | 1.9 × 0.2 × 1.2 | 287.05 | 288.25 | 0.456 | office_0172 | yes | 0.456924 | 1.90953 | 1.2 | 5.8 | 0.456 | office | Edificio de oficinas | {"name":"Bloque hueco de hormigón de árido ligero","source":"ARQ-OF-20260710 · Arquitectura A101 / p. 3, A103 / p. 5, A106 / p. 8; A301Cuadro de materiales ","status":"known"} | {"documented":[{"label":"Espesor del muro","value":0.2,"unit":"m","source":"ARQ-OF-20260710 · Arquitectura A101 / p. 3, A103 / p. 5, A106 / p. 8; A301Cuadro de materiales ","status":"documentado"}],"geometry":[{"label":"Dimensiones de la caja local del elemento (X, Y, Z)","value":"1.9 × 0.2 × 1.2","unit":"m","source":"Malla triangulada del elemento en ejes locales del edificio","status":"derivado"},{"label":"Cota mínima absoluta de la malla","value":287.05,"unit":"m","source":"Malla de proyecto y origen altimétrico 285 m","status":"derivado"},{"label":"Cota máxima absoluta de la malla","value":288.25,"unit":"m","source":"Malla de proyecto y origen altimétrico 285 m","status":"derivado"},{"label":"Volumen geométrico bruto","value":0.456,"unit":"m³","source":"Malla cerrada del elemento","status":"derivado"}],"notes":["Las dimensiones documentadas proceden de anotaciones o cuadros; la caja y el volumen se calculan a partir de la malla.","El volumen es exclusivamente geométrico y bruto; no representa una medición neta de material ni una cantidad de compra."]} | {"documentId":"ARQ-OF-20260710","title":"Planos de arquitectura del edificio de oficinas","date":"2026-07-10","sheet":"Arquitectura A101 / p. 3, A103 / p. 5, A106 / p. 8; A301Cuadro de materiales "} | ["El plano general de 2026-07-31 mantiene el edificio de oficinas de 200 m², mientras documentación anterior indica su supresión. Se conserva lo dibujado, pendiente de confirmación de la propiedad y del equipo de diseño.","Envolvente exterior controlada por la planta de arquitectura; no se han modelado individualmente todas las capas de acabado.","Registro de líneas del PDF general, envolvente de 20 × 10 m; eje local 1 al norte y acceso del lado A al oeste. Estimación de trabajo de implantación de ±0,15 m, pendiente de CAD; no constituye una precisión topográfica garantizada."] | {"horizontalStatus":"derivado","verticalStatus":"derivado","baseElevationM":285.95,"note":"Registro de líneas del PDF general, envolvente de 20 × 10 m; eje local 1 al norte y acceso del lado A al oeste. Estimación de trabajo de implantación de ±0,15 m, pendiente de CAD; no constituye una precisión topográfica garantizada."} | {"Pset_WallCommon":{"IsExternal":{"value":true,"source":"ARQ-OF-20260710 · A101, A103 y alzados; elemento de la envolvente exterior identificada en planta","status":"known"}}} | {"boundingBoxM":{"min":[24.717914,73.129125,2.05],"max":[25.174838,75.03866,3.25]},"extentsM":[0.456924,1.909535,1.2],"meshSurfaceM2":5.800001,"meshVolumeM3":0.456,"closedSolid":true,"basis":"Geometría triangulada releída del IFC; envolventes y magnitudes no contractuales."} | {"material":true,"document":true,"quantities":true,"containerGuid":"3ztlotcerHPueDgxP84R6z","containerName":"Planta baja"} | {"id":"architecture","name":"Arquitectura"} | {"profileId":"block_masonry","name":"Fábrica de bloques · acabado mineral claro","materialName":"Bloque hueco de hormigón de árido ligero","physicalMaterialStatus":"known","physicalMaterialSource":"ARQ-OF-20260710 · Arquitectura A101 / p. 3, A103 / p. 5, A106 / p. 8; A301Cuadro de materiales ","appearanceStatus":"criterio_visual","appearanceBasis":"Bloque hueco documentado. Apariencia mineral clara para distinguir el cerramiento; no confirma un revoco ni su espesor.","note":"La apariencia gráfica no modifica ni confirma la especificación física del material."} | {"elementId":"office_0172","ifcGuid":"3Q_qULz0DLLeWOdiodqlNr","ifcClass":"IfcWall","buildingId":"office","buildingName":"Edificio de oficinas","sourceDocumentId":"ARQ-OF-20260710","sourceRepresentationKind":"documentary_mesh"} | {"layerId":"architecture","layerName":"Arquitectura","role":"Muro","basis":"Clasificación por función del elemento; no modifica las especificaciones documentales."} | architecture | {"profileId":"block_masonry","name":"Fábrica de bloques · acabado mineral claro","status":"criterio_visual","basis":"Bloque hueco documentado. Apariencia mineral clara para distinguir el cerramiento; no confirma un revoco ni su espesor.","physicalMaterialUnchanged":true} | ARQ-OF-20260710 · Arquitectura A101 / p. 3, A103 / p. 5, A106 / p. 8; A301Cuadro de materiales | Dimensiones contrastadas con los planos; reconstrucción geométrica a partir de documentación de diseño. | 0.2 | Muros segmentados con huecos reales para puertas y ventanas. | Envolvente exterior controlada por la planta de arquitectura; no se han modelado individualmente todas las capas de acabado. | Registro de líneas del PDF general, envolvente de 20 × 10 m; eje local 1 al norte y acceso del lado A al oeste. Estimación de trabajo de implantación de ±0,15 m, pendiente de CAD; no constituye una precisión topográfica garantizada. | Arquitectura | ARQ-OF-20260710 · Arquitectura A101 / p. 3, A103 / p. 5, A106 / p. 8; A301Cuadro de materiales | 285.95 | Arquitectura | Fábrica de bloques · acabado mineral claro | block_masonry | [0.843137,0.823529,0.772549] | 0.96 | 0 | Bloque hueco documentado. Apariencia mineral clara para distinguir el cerramiento; no confirma un revoco ni su espesor. | Arquitectura; BIM · Arquitectura | El plano general de 2026-07-31 mantiene el edificio de oficinas de 200 m², mientras documentación anterior indica su supresión. Se conserva lo dibujado, pendiente de confirmación de la propiedad y del equipo de diseño.
Edificio de oficinas · Fábrica de bloques huecos de hormigón de 200 mm · eje B · tramo 51 | Planos de arquitectura del edificio de oficinas | Bloque hueco de hormigón de árido ligero | 1.9 × 0.2 × 1.1 | 288.25 | 289.35 | 0.418 | office_0173 | yes | 0.456924 | 1.90953 | 1.1 | 5.38 | 0.418 | office | Edificio de oficinas | {"name":"Bloque hueco de hormigón de árido ligero","source":"ARQ-OF-20260710 · Arquitectura A101 / p. 3, A103 / p. 5, A106 / p. 8; A301Cuadro de materiales ","status":"known"} | {"documented":[{"label":"Espesor del muro","value":0.2,"unit":"m","source":"ARQ-OF-20260710 · Arquitectura A101 / p. 3, A103 / p. 5, A106 / p. 8; A301Cuadro de materiales ","status":"documentado"}],"geometry":[{"label":"Dimensiones de la caja local del elemento (X, Y, Z)","value":"1.9 × 0.2 × 1.1","unit":"m","source":"Malla triangulada del elemento en ejes locales del edificio","status":"derivado"},{"label":"Cota mínima absoluta de la malla","value":288.25,"unit":"m","source":"Malla de proyecto y origen altimétrico 285 m","status":"derivado"},{"label":"Cota máxima absoluta de la malla","value":289.35,"unit":"m","source":"Malla de proyecto y origen altimétrico 285 m","status":"derivado"},{"label":"Volumen geométrico bruto","value":0.418,"unit":"m³","source":"Malla cerrada del elemento","status":"derivado"}],"notes":["Las dimensiones documentadas proceden de anotaciones o cuadros; la caja y el volumen se calculan a partir de la malla.","El volumen es exclusivamente geométrico y bruto; no representa una medición neta de material ni una cantidad de compra."]} | {"documentId":"ARQ-OF-20260710","title":"Planos de arquitectura del edificio de oficinas","date":"2026-07-10","sheet":"Arquitectura A101 / p. 3, A103 / p. 5, A106 / p. 8; A301Cuadro de materiales "} | ["El plano general de 2026-07-31 mantiene el edificio de oficinas de 200 m², mientras documentación anterior indica su supresión. Se conserva lo dibujado, pendiente de confirmación de la propiedad y del equipo de diseño.","Envolvente exterior controlada por la planta de arquitectura; no se han modelado individualmente todas las capas de acabado.","Registro de líneas del PDF general, envolvente de 20 × 10 m; eje local 1 al norte y acceso del lado A al oeste. Estimación de trabajo de implantación de ±0,15 m, pendiente de CAD; no constituye una precisión topográfica garantizada."] | {"horizontalStatus":"derivado","verticalStatus":"derivado","baseElevationM":285.95,"note":"Registro de líneas del PDF general, envolvente de 20 × 10 m; eje local 1 al norte y acceso del lado A al oeste. Estimación de trabajo de implantación de ±0,15 m, pendiente de CAD; no constituye una precisión topográfica garantizada."} | {"Pset_WallCommon":{"IsExternal":{"value":true,"source":"ARQ-OF-20260710 · A101, A103 y alzados; elemento de la envolvente exterior identificada en planta","status":"known"}}} | {"boundingBoxM":{"min":[24.717914,73.129125,3.25],"max":[25.174838,75.03866,4.35]},"extentsM":[0.456924,1.909535,1.1],"meshSurfaceM2":5.380001,"meshVolumeM3":0.418,"closedSolid":true,"basis":"Geometría triangulada releída del IFC; envolventes y magnitudes no contractuales."} | {"material":true,"document":true,"quantities":true,"containerGuid":"3ztlotcerHPueDgxP84R6z","containerName":"Planta baja"} | {"id":"architecture","name":"Arquitectura"} | {"profileId":"block_masonry","name":"Fábrica de bloques · acabado mineral claro","materialName":"Bloque hueco de hormigón de árido ligero","physicalMaterialStatus":"known","physicalMaterialSource":"ARQ-OF-20260710 · Arquitectura A101 / p. 3, A103 / p. 5, A106 / p. 8; A301Cuadro de materiales ","appearanceStatus":"criterio_visual","appearanceBasis":"Bloque hueco documentado. Apariencia mineral clara para distinguir el cerramiento; no confirma un revoco ni su espesor.","note":"La apariencia gráfica no modifica ni confirma la especificación física del material."} | {"elementId":"office_0173","ifcGuid":"3iUhwOJwvIaR_3nhLy7nZx","ifcClass":"IfcWall","buildingId":"office","buildingName":"Edificio de oficinas","sourceDocumentId":"ARQ-OF-20260710","sourceRepresentationKind":"documentary_mesh"} | {"layerId":"architecture","layerName":"Arquitectura","role":"Muro","basis":"Clasificación por función del elemento; no modifica las especificaciones documentales."} | architecture | {"profileId":"block_masonry","name":"Fábrica de bloques · acabado mineral claro","status":"criterio_visual","basis":"Bloque hueco documentado. Apariencia mineral clara para distinguir el cerramiento; no confirma un revoco ni su espesor.","physicalMaterialUnchanged":true} | ARQ-OF-20260710 · Arquitectura A101 / p. 3, A103 / p. 5, A106 / p. 8; A301Cuadro de materiales | Dimensiones contrastadas con los planos; reconstrucción geométrica a partir de documentación de diseño. | 0.2 | Muros segmentados con huecos reales para puertas y ventanas. | Envolvente exterior controlada por la planta de arquitectura; no se han modelado individualmente todas las capas de acabado. | Registro de líneas del PDF general, envolvente de 20 × 10 m; eje local 1 al norte y acceso del lado A al oeste. Estimación de trabajo de implantación de ±0,15 m, pendiente de CAD; no constituye una precisión topográfica garantizada. | Arquitectura | ARQ-OF-20260710 · Arquitectura A101 / p. 3, A103 / p. 5, A106 / p. 8; A301Cuadro de materiales | 285.95 | Arquitectura | Fábrica de bloques · acabado mineral claro | block_masonry | [0.843137,0.823529,0.772549] | 0.96 | 0 | Bloque hueco documentado. Apariencia mineral clara para distinguir el cerramiento; no confirma un revoco ni su espesor. | Arquitectura; BIM · Arquitectura | El plano general de 2026-07-31 mantiene el edificio de oficinas de 200 m², mientras documentación anterior indica su supresión. Se conserva lo dibujado, pendiente de confirmación de la propiedad y del equipo de diseño.
Edificio de oficinas · Fábrica de bloques huecos de hormigón de 200 mm · eje B · tramo 52 | Planos de arquitectura del edificio de oficinas | Bloque hueco de hormigón de árido ligero | 1.9 × 0.2 × 1.6 | 289.35 | 290.95 | 0.608 | office_0174 | yes | 0.456924 | 1.90953 | 1.6 | 7.48 | 0.608 | office | Edificio de oficinas | {"name":"Bloque hueco de hormigón de árido ligero","source":"ARQ-OF-20260710 · Arquitectura A101 / p. 3, A103 / p. 5, A106 / p. 8; A301Cuadro de materiales ","status":"known"} | {"documented":[{"label":"Espesor del muro","value":0.2,"unit":"m","source":"ARQ-OF-20260710 · Arquitectura A101 / p. 3, A103 / p. 5, A106 / p. 8; A301Cuadro de materiales ","status":"documentado"}],"geometry":[{"label":"Dimensiones de la caja local del elemento (X, Y, Z)","value":"1.9 × 0.2 × 1.6","unit":"m","source":"Malla triangulada del elemento en ejes locales del edificio","status":"derivado"},{"label":"Cota mínima absoluta de la malla","value":289.35,"unit":"m","source":"Malla de proyecto y origen altimétrico 285 m","status":"derivado"},{"label":"Cota máxima absoluta de la malla","value":290.95,"unit":"m","source":"Malla de proyecto y origen altimétrico 285 m","status":"derivado"},{"label":"Volumen geométrico bruto","value":0.608,"unit":"m³","source":"Malla cerrada del elemento","status":"derivado"}],"notes":["Las dimensiones documentadas proceden de anotaciones o cuadros; la caja y el volumen se calculan a partir de la malla.","El volumen es exclusivamente geométrico y bruto; no representa una medición neta de material ni una cantidad de compra."]} | {"documentId":"ARQ-OF-20260710","title":"Planos de arquitectura del edificio de oficinas","date":"2026-07-10","sheet":"Arquitectura A101 / p. 3, A103 / p. 5, A106 / p. 8; A301Cuadro de materiales "} | ["El plano general de 2026-07-31 mantiene el edificio de oficinas de 200 m², mientras documentación anterior indica su supresión. Se conserva lo dibujado, pendiente de confirmación de la propiedad y del equipo de diseño.","Envolvente exterior controlada por la planta de arquitectura; no se han modelado individualmente todas las capas de acabado.","Registro de líneas del PDF general, envolvente de 20 × 10 m; eje local 1 al norte y acceso del lado A al oeste. Estimación de trabajo de implantación de ±0,15 m, pendiente de CAD; no constituye una precisión topográfica garantizada."] | {"horizontalStatus":"derivado","verticalStatus":"derivado","baseElevationM":285.95,"note":"Registro de líneas del PDF general, envolvente de 20 × 10 m; eje local 1 al norte y acceso del lado A al oeste. Estimación de trabajo de implantación de ±0,15 m, pendiente de CAD; no constituye una precisión topográfica garantizada."} | {"Pset_WallCommon":{"IsExternal":{"value":true,"source":"ARQ-OF-20260710 · A101, A103 y alzados; elemento de la envolvente exterior identificada en planta","status":"known"}}} | {"boundingBoxM":{"min":[24.717914,73.129125,4.35],"max":[25.174838,75.03866,5.95]},"extentsM":[0.456924,1.909535,1.6],"meshSurfaceM2":7.480001,"meshVolumeM3":0.608,"closedSolid":true,"basis":"Geometría triangulada releída del IFC; envolventes y magnitudes no contractuales."} | {"material":true,"document":true,"quantities":true,"containerGuid":"3ztlotcerHPueDgxP84R6z","containerName":"Planta baja"} | {"id":"architecture","name":"Arquitectura"} | {"profileId":"block_masonry","name":"Fábrica de bloques · acabado mineral claro","materialName":"Bloque hueco de hormigón de árido ligero","physicalMaterialStatus":"known","physicalMaterialSource":"ARQ-OF-20260710 · Arquitectura A101 / p. 3, A103 / p. 5, A106 / p. 8; A301Cuadro de materiales ","appearanceStatus":"criterio_visual","appearanceBasis":"Bloque hueco documentado. Apariencia mineral clara para distinguir el cerramiento; no confirma un revoco ni su espesor.","note":"La apariencia gráfica no modifica ni confirma la especificación física del material."} | {"elementId":"office_0174","ifcGuid":"0VjYtQAzDVzuCwZ0y6gtzr","ifcClass":"IfcWall","buildingId":"office","buildingName":"Edificio de oficinas","sourceDocumentId":"ARQ-OF-20260710","sourceRepresentationKind":"documentary_mesh"} | {"layerId":"architecture","layerName":"Arquitectura","role":"Muro","basis":"Clasificación por función del elemento; no modifica las especificaciones documentales."} | architecture | {"profileId":"block_masonry","name":"Fábrica de bloques · acabado mineral claro","status":"criterio_visual","basis":"Bloque hueco documentado. Apariencia mineral clara para distinguir el cerramiento; no confirma un revoco ni su espesor.","physicalMaterialUnchanged":true} | ARQ-OF-20260710 · Arquitectura A101 / p. 3, A103 / p. 5, A106 / p. 8; A301Cuadro de materiales | Dimensiones contrastadas con los planos; reconstrucción geométrica a partir de documentación de diseño. | 0.2 | Muros segmentados con huecos reales para puertas y ventanas. | Envolvente exterior controlada por la planta de arquitectura; no se han modelado individualmente todas las capas de acabado. | Registro de líneas del PDF general, envolvente de 20 × 10 m; eje local 1 al norte y acceso del lado A al oeste. Estimación de trabajo de implantación de ±0,15 m, pendiente de CAD; no constituye una precisión topográfica garantizada. | Arquitectura | ARQ-OF-20260710 · Arquitectura A101 / p. 3, A103 / p. 5, A106 / p. 8; A301Cuadro de materiales | 285.95 | Arquitectura | Fábrica de bloques · acabado mineral claro | block_masonry | [0.843137,0.823529,0.772549] | 0.96 | 0 | Bloque hueco documentado. Apariencia mineral clara para distinguir el cerramiento; no confirma un revoco ni su espesor. | Arquitectura; BIM · Arquitectura | El plano general de 2026-07-31 mantiene el edificio de oficinas de 200 m², mientras documentación anterior indica su supresión. Se conserva lo dibujado, pendiente de confirmación de la propiedad y del equipo de diseño.
Edificio de oficinas · Fábrica de bloques huecos de hormigón de 200 mm · eje B · tramo 53 | Planos de arquitectura del edificio de oficinas | Bloque hueco de hormigón de árido ligero | 0.6 × 0.2 × 1.1 | 285.95 | 287.05 | 0.132 | office_0175 | yes | 0.279858 | 0.621649 | 1.1 | 2 | 0.132 | office | Edificio de oficinas | {"name":"Bloque hueco de hormigón de árido ligero","source":"ARQ-OF-20260710 · Arquitectura A101 / p. 3, A103 / p. 5, A106 / p. 8; A301Cuadro de materiales ","status":"known"} | {"documented":[{"label":"Espesor del muro","value":0.2,"unit":"m","source":"ARQ-OF-20260710 · Arquitectura A101 / p. 3, A103 / p. 5, A106 / p. 8; A301Cuadro de materiales ","status":"documentado"}],"geometry":[{"label":"Dimensiones de la caja local del elemento (X, Y, Z)","value":"0.6 × 0.2 × 1.1","unit":"m","source":"Malla triangulada del elemento en ejes locales del edificio","status":"derivado"},{"label":"Cota mínima absoluta de la malla","value":285.95,"unit":"m","source":"Malla de proyecto y origen altimétrico 285 m","status":"derivado"},{"label":"Cota máxima absoluta de la malla","value":287.05,"unit":"m","source":"Malla de proyecto y origen altimétrico 285 m","status":"derivado"},{"label":"Volumen geométrico bruto","value":0.132,"unit":"m³","source":"Malla cerrada del elemento","status":"derivado"}],"notes":["Las dimensiones documentadas proceden de anotaciones o cuadros; la caja y el volumen se calculan a partir de la malla.","El volumen es exclusivamente geométrico y bruto; no representa una medición neta de material ni una cantidad de compra."]} | {"documentId":"ARQ-OF-20260710","title":"Planos de arquitectura del edificio de oficinas","date":"2026-07-10","sheet":"Arquitectura A101 / p. 3, A103 / p. 5, A106 / p. 8; A301Cuadro de materiales "} | ["El plano general de 2026-07-31 mantiene el edificio de oficinas de 200 m², mientras documentación anterior indica su supresión. Se conserva lo dibujado, pendiente de confirmación de la propiedad y del equipo de diseño.","Envolvente exterior controlada por la planta de arquitectura; no se han modelado individualmente todas las capas de acabado.","Registro de líneas del PDF general, envolvente de 20 × 10 m; eje local 1 al norte y acceso del lado A al oeste. Estimación de trabajo de implantación de ±0,15 m, pendiente de CAD; no constituye una precisión topográfica garantizada."] | {"horizontalStatus":"derivado","verticalStatus":"derivado","baseElevationM":285.95,"note":"Registro de líneas del PDF general, envolvente de 20 × 10 m; eje local 1 al norte y acceso del lado A al oeste. Estimación de trabajo de implantación de ±0,15 m, pendiente de CAD; no constituye una precisión topográfica garantizada."} | {"Pset_WallCommon":{"IsExternal":{"value":true,"source":"ARQ-OF-20260710 · A101, A103 y alzados; elemento de la envolvente exterior identificada en planta","status":"known"}}} | {"boundingBoxM":{"min":[24.636192,72.534717,0.95],"max":[24.91605,73.156366,2.05]},"extentsM":[0.279858,0.621649,1.1],"meshSurfaceM2":1.999998,"meshVolumeM3":0.132,"closedSolid":true,"basis":"Geometría triangulada releída del IFC; envolventes y magnitudes no contractuales."} | {"material":true,"document":true,"quantities":true,"containerGuid":"3ztlotcerHPueDgxP84R6z","containerName":"Planta baja"} | {"id":"architecture","name":"Arquitectura"} | {"profileId":"block_masonry","name":"Fábrica de bloques · acabado mineral claro","materialName":"Bloque hueco de hormigón de árido ligero","physicalMaterialStatus":"known","physicalMaterialSource":"ARQ-OF-20260710 · Arquitectura A101 / p. 3, A103 / p. 5, A106 / p. 8; A301Cuadro de materiales ","appearanceStatus":"criterio_visual","appearanceBasis":"Bloque hueco documentado. Apariencia mineral clara para distinguir el cerramiento; no confirma un revoco ni su espesor.","note":"La apariencia gráfica no modifica ni confirma la especificación física del material."} | {"elementId":"office_0175","ifcGuid":"3J6onsUQjMG8_4caMz$$sX","ifcClass":"IfcWall","buildingId":"office","buildingName":"Edificio de oficinas","sourceDocumentId":"ARQ-OF-20260710","sourceRepresentationKind":"documentary_mesh"} | {"layerId":"architecture","layerName":"Arquitectura","role":"Muro","basis":"Clasificación por función del elemento; no modifica las especificaciones documentales."} | architecture | {"profileId":"block_masonry","name":"Fábrica de bloques · acabado mineral claro","status":"criterio_visual","basis":"Bloque hueco documentado. Apariencia mineral clara para distinguir el cerramiento; no confirma un revoco ni su espesor.","physicalMaterialUnchanged":true} | ARQ-OF-20260710 · Arquitectura A101 / p. 3, A103 / p. 5, A106 / p. 8; A301Cuadro de materiales | Dimensiones contrastadas con los planos; reconstrucción geométrica a partir de documentación de diseño. | 0.2 | Muros segmentados con huecos reales para puertas y ventanas. | Envolvente exterior controlada por la planta de arquitectura; no se han modelado individualmente todas las capas de acabado. | Registro de líneas del PDF general, envolvente de 20 × 10 m; eje local 1 al norte y acceso del lado A al oeste. Estimación de trabajo de implantación de ±0,15 m, pendiente de CAD; no constituye una precisión topográfica garantizada. | Arquitectura | ARQ-OF-20260710 · Arquitectura A101 / p. 3, A103 / p. 5, A106 / p. 8; A301Cuadro de materiales | 285.95 | Arquitectura | Fábrica de bloques · acabado mineral claro | block_masonry | [0.843137,0.823529,0.772549] | 0.96 | 0 | Bloque hueco documentado. Apariencia mineral clara para distinguir el cerramiento; no confirma un revoco ni su espesor. | Arquitectura; BIM · Arquitectura | El plano general de 2026-07-31 mantiene el edificio de oficinas de 200 m², mientras documentación anterior indica su supresión. Se conserva lo dibujado, pendiente de confirmación de la propiedad y del equipo de diseño.
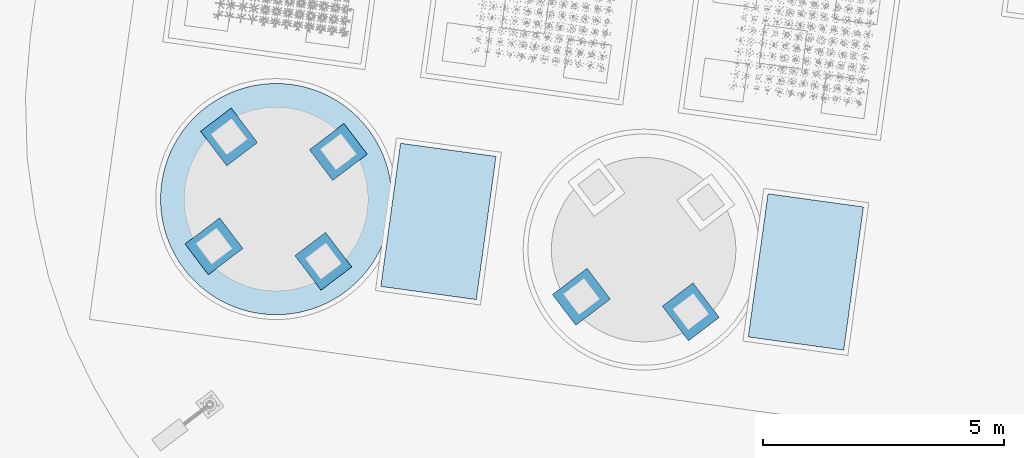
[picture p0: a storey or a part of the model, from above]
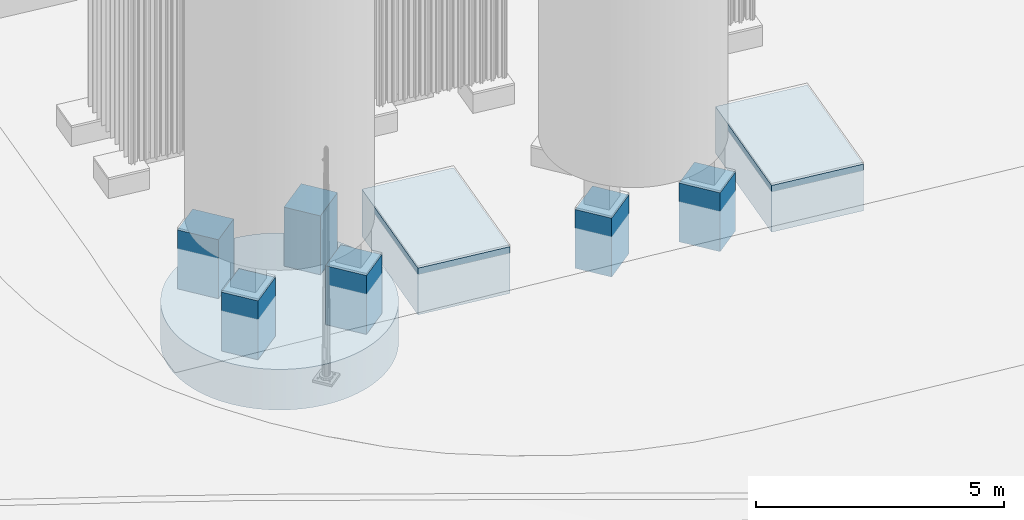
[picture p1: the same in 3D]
Properties of the parts of a building model (IFC4), part 128 of 134

# IfcWall (187)
Name | Document | Material = JH_Trazabilidad, Material = name | Dimensiones de la caja local del elemento (X, Y, Z) | Cota mínima absoluta de la malla (m) | Cota máxima absoluta de la malla (m) | Volumen geométrico bruto (m3) = Volumen geométrico (m³) | Reference = Identificador del elemento = Identificador | IsExternal | ExtensionX (m) | ExtensionY (m) | ExtensionZ (m) | SuperficieDeLaMalla (m2) | VolumenGeometrico (m3) = GrossVolume (m3) | buildingId | buildingName = Edificio | material | dimensions | JH_InformacionBIM, source = DocumentoFuente | issues = IncidenciasPendientes | positioning = PosicionYEstado | commonProperties | geometryMetrics | ifcAssociations | visualLayer | materialAppearance | visualizationIdentity | classification | layerId = IdentificadorCapa | appearance | Planos de referencia | Base geométrica | Espesor del muro (m) = Espesor del muro (m) | Tratamiento de los huecos | Representación de los acabados | Estado de la implantación | Disciplina | Referencia del material = JH_EvidenciaDeMaterial, source | Cota de planta baja terminada (m) | Capa BIM = NombreCapa | Acabado de visualización = Acabado | Perfil | ColorRGB | Rugosidad | Metallicidad | Referencia | Group | Discrepancia entre versiones
Edificio de oficinas · Fábrica de bloques huecos de hormigón de 200 mm · eje B · tramo 54 | Planos de arquitectura del edificio de oficinas | Bloque hueco de hormigón de árido ligero | 0.6 × 0.2 × 1.6 | 289.35 | 290.95 | 0.192 | office_0176 | yes | 0.279858 | 0.621649 | 1.6 | 2.8 | 0.192 | office | Edificio de oficinas | {"name":"Bloque hueco de hormigón de árido ligero","source":"ARQ-OF-20260710 · Arquitectura A101 / p. 3, A103 / p. 5, A106 / p. 8; A301Cuadro de materiales ","status":"known"} | {"documented":[{"label":"Espesor del muro","value":0.2,"unit":"m","source":"ARQ-OF-20260710 · Arquitectura A101 / p. 3, A103 / p. 5, A106 / p. 8; A301Cuadro de materiales ","status":"documentado"}],"geometry":[{"label":"Dimensiones de la caja local del elemento (X, Y, Z)","value":"0.6 × 0.2 × 1.6","unit":"m","source":"Malla triangulada del elemento en ejes locales del edificio","status":"derivado"},{"label":"Cota mínima absoluta de la malla","value":289.35,"unit":"m","source":"Malla de proyecto y origen altimétrico 285 m","status":"derivado"},{"label":"Cota máxima absoluta de la malla","value":290.95,"unit":"m","source":"Malla de proyecto y origen altimétrico 285 m","status":"derivado"},{"label":"Volumen geométrico bruto","value":0.192,"unit":"m³","source":"Malla cerrada del elemento","status":"derivado"}],"notes":["Las dimensiones documentadas proceden de anotaciones o cuadros; la caja y el volumen se calculan a partir de la malla.","El volumen es exclusivamente geométrico y bruto; no representa una medición neta de material ni una cantidad de compra."]} | {"documentId":"ARQ-OF-20260710","title":"Planos de arquitectura del edificio de oficinas","date":"2026-07-10","sheet":"Arquitectura A101 / p. 3, A103 / p. 5, A106 / p. 8; A301Cuadro de materiales "} | ["El plano general de 2026-07-31 mantiene el edificio de oficinas de 200 m², mientras documentación anterior indica su supresión. Se conserva lo dibujado, pendiente de confirmación de la propiedad y del equipo de diseño.","Envolvente exterior controlada por la planta de arquitectura; no se han modelado individualmente todas las capas de acabado.","Registro de líneas del PDF general, envolvente de 20 × 10 m; eje local 1 al norte y acceso del lado A al oeste. Estimación de trabajo de implantación de ±0,15 m, pendiente de CAD; no constituye una precisión topográfica garantizada."] | {"horizontalStatus":"derivado","verticalStatus":"derivado","baseElevationM":285.95,"note":"Registro de líneas del PDF general, envolvente de 20 × 10 m; eje local 1 al norte y acceso del lado A al oeste. Estimación de trabajo de implantación de ±0,15 m, pendiente de CAD; no constituye una precisión topográfica garantizada."} | {"Pset_WallCommon":{"IsExternal":{"value":true,"source":"ARQ-OF-20260710 · A101, A103 y alzados; elemento de la envolvente exterior identificada en planta","status":"known"}}} | {"boundingBoxM":{"min":[24.636192,72.534717,4.35],"max":[24.91605,73.156366,5.95]},"extentsM":[0.279858,0.621649,1.6],"meshSurfaceM2":2.799997,"meshVolumeM3":0.192,"closedSolid":true,"basis":"Geometría triangulada releída del IFC; envolventes y magnitudes no contractuales."} | {"material":true,"document":true,"quantities":true,"containerGuid":"3ztlotcerHPueDgxP84R6z","containerName":"Planta baja"} | {"id":"architecture","name":"Arquitectura"} | {"profileId":"block_masonry","name":"Fábrica de bloques · acabado mineral claro","materialName":"Bloque hueco de hormigón de árido ligero","physicalMaterialStatus":"known","physicalMaterialSource":"ARQ-OF-20260710 · Arquitectura A101 / p. 3, A103 / p. 5, A106 / p. 8; A301Cuadro de materiales ","appearanceStatus":"criterio_visual","appearanceBasis":"Bloque hueco documentado. Apariencia mineral clara para distinguir el cerramiento; no confirma un revoco ni su espesor.","note":"La apariencia gráfica no modifica ni confirma la especificación física del material."} | {"elementId":"office_0176","ifcGuid":"0OOeSWZBjHkR9gkvtyVOem","ifcClass":"IfcWall","buildingId":"office","buildingName":"Edificio de oficinas","sourceDocumentId":"ARQ-OF-20260710","sourceRepresentationKind":"documentary_mesh"} | {"layerId":"architecture","layerName":"Arquitectura","role":"Muro","basis":"Clasificación por función del elemento; no modifica las especificaciones documentales."} | architecture | {"profileId":"block_masonry","name":"Fábrica de bloques · acabado mineral claro","status":"criterio_visual","basis":"Bloque hueco documentado. Apariencia mineral clara para distinguir el cerramiento; no confirma un revoco ni su espesor.","physicalMaterialUnchanged":true} | ARQ-OF-20260710 · Arquitectura A101 / p. 3, A103 / p. 5, A106 / p. 8; A301Cuadro de materiales | Dimensiones contrastadas con los planos; reconstrucción geométrica a partir de documentación de diseño. | 0.2 | Muros segmentados con huecos reales para puertas y ventanas. | Envolvente exterior controlada por la planta de arquitectura; no se han modelado individualmente todas las capas de acabado. | Registro de líneas del PDF general, envolvente de 20 × 10 m; eje local 1 al norte y acceso del lado A al oeste. Estimación de trabajo de implantación de ±0,15 m, pendiente de CAD; no constituye una precisión topográfica garantizada. | Arquitectura | ARQ-OF-20260710 · Arquitectura A101 / p. 3, A103 / p. 5, A106 / p. 8; A301Cuadro de materiales | 285.95 | Arquitectura | Fábrica de bloques · acabado mineral claro | block_masonry | [0.843137,0.823529,0.772549] | 0.96 | 0 | Bloque hueco documentado. Apariencia mineral clara para distinguir el cerramiento; no confirma un revoco ni su espesor. | Arquitectura; BIM · Arquitectura | El plano general de 2026-07-31 mantiene el edificio de oficinas de 200 m², mientras documentación anterior indica su supresión. Se conserva lo dibujado, pendiente de confirmación de la propiedad y del equipo de diseño.
Edificio de oficinas · Fábrica de bloques huecos de hormigón de 200 mm · eje B · tramo 55 | Planos de arquitectura del edificio de oficinas | Bloque hueco de hormigón de árido ligero | 0.8 × 0.2 × 1.1 | 285.95 | 287.05 | 0.176 | office_0177 | yes | 0.307099 | 0.819786 | 1.1 | 2.52 | 0.176 | office | Edificio de oficinas | {"name":"Bloque hueco de hormigón de árido ligero","source":"ARQ-OF-20260710 · Arquitectura A101 / p. 3, A103 / p. 5, A106 / p. 8; A301Cuadro de materiales ","status":"known"} | {"documented":[{"label":"Espesor del muro","value":0.2,"unit":"m","source":"ARQ-OF-20260710 · Arquitectura A101 / p. 3, A103 / p. 5, A106 / p. 8; A301Cuadro de materiales ","status":"documentado"}],"geometry":[{"label":"Dimensiones de la caja local del elemento (X, Y, Z)","value":"0.8 × 0.2 × 1.1","unit":"m","source":"Malla triangulada del elemento en ejes locales del edificio","status":"derivado"},{"label":"Cota mínima absoluta de la malla","value":285.95,"unit":"m","source":"Malla de proyecto y origen altimétrico 285 m","status":"derivado"},{"label":"Cota máxima absoluta de la malla","value":287.05,"unit":"m","source":"Malla de proyecto y origen altimétrico 285 m","status":"derivado"},{"label":"Volumen geométrico bruto","value":0.176,"unit":"m³","source":"Malla cerrada del elemento","status":"derivado"}],"notes":["Las dimensiones documentadas proceden de anotaciones o cuadros; la caja y el volumen se calculan a partir de la malla.","El volumen es exclusivamente geométrico y bruto; no representa una medición neta de material ni una cantidad de compra."]} | {"documentId":"ARQ-OF-20260710","title":"Planos de arquitectura del edificio de oficinas","date":"2026-07-10","sheet":"Arquitectura A101 / p. 3, A103 / p. 5, A106 / p. 8; A301Cuadro de materiales "} | ["El plano general de 2026-07-31 mantiene el edificio de oficinas de 200 m², mientras documentación anterior indica su supresión. Se conserva lo dibujado, pendiente de confirmación de la propiedad y del equipo de diseño.","Envolvente exterior controlada por la planta de arquitectura; no se han modelado individualmente todas las capas de acabado.","Registro de líneas del PDF general, envolvente de 20 × 10 m; eje local 1 al norte y acceso del lado A al oeste. Estimación de trabajo de implantación de ±0,15 m, pendiente de CAD; no constituye una precisión topográfica garantizada."] | {"horizontalStatus":"derivado","verticalStatus":"derivado","baseElevationM":285.95,"note":"Registro de líneas del PDF general, envolvente de 20 × 10 m; eje local 1 al norte y acceso del lado A al oeste. Estimación de trabajo de implantación de ±0,15 m, pendiente de CAD; no constituye una precisión topográfica garantizada."} | {"Pset_WallCommon":{"IsExternal":{"value":true,"source":"ARQ-OF-20260710 · A101, A103 y alzados; elemento de la envolvente exterior identificada en planta","status":"known"}}} | {"boundingBoxM":{"min":[24.527229,71.742172,0.95],"max":[24.834328,72.561958,2.05]},"extentsM":[0.307099,0.819786,1.1],"meshSurfaceM2":2.52,"meshVolumeM3":0.176,"closedSolid":true,"basis":"Geometría triangulada releída del IFC; envolventes y magnitudes no contractuales."} | {"material":true,"document":true,"quantities":true,"containerGuid":"3ztlotcerHPueDgxP84R6z","containerName":"Planta baja"} | {"id":"architecture","name":"Arquitectura"} | {"profileId":"block_masonry","name":"Fábrica de bloques · acabado mineral claro","materialName":"Bloque hueco de hormigón de árido ligero","physicalMaterialStatus":"known","physicalMaterialSource":"ARQ-OF-20260710 · Arquitectura A101 / p. 3, A103 / p. 5, A106 / p. 8; A301Cuadro de materiales ","appearanceStatus":"criterio_visual","appearanceBasis":"Bloque hueco documentado. Apariencia mineral clara para distinguir el cerramiento; no confirma un revoco ni su espesor.","note":"La apariencia gráfica no modifica ni confirma la especificación física del material."} | {"elementId":"office_0177","ifcGuid":"226KXXV_HG4wDparIgsKbP","ifcClass":"IfcWall","buildingId":"office","buildingName":"Edificio de oficinas","sourceDocumentId":"ARQ-OF-20260710","sourceRepresentationKind":"documentary_mesh"} | {"layerId":"architecture","layerName":"Arquitectura","role":"Muro","basis":"Clasificación por función del elemento; no modifica las especificaciones documentales."} | architecture | {"profileId":"block_masonry","name":"Fábrica de bloques · acabado mineral claro","status":"criterio_visual","basis":"Bloque hueco documentado. Apariencia mineral clara para distinguir el cerramiento; no confirma un revoco ni su espesor.","physicalMaterialUnchanged":true} | ARQ-OF-20260710 · Arquitectura A101 / p. 3, A103 / p. 5, A106 / p. 8; A301Cuadro de materiales | Dimensiones contrastadas con los planos; reconstrucción geométrica a partir de documentación de diseño. | 0.2 | Muros segmentados con huecos reales para puertas y ventanas. | Envolvente exterior controlada por la planta de arquitectura; no se han modelado individualmente todas las capas de acabado. | Registro de líneas del PDF general, envolvente de 20 × 10 m; eje local 1 al norte y acceso del lado A al oeste. Estimación de trabajo de implantación de ±0,15 m, pendiente de CAD; no constituye una precisión topográfica garantizada. | Arquitectura | ARQ-OF-20260710 · Arquitectura A101 / p. 3, A103 / p. 5, A106 / p. 8; A301Cuadro de materiales | 285.95 | Arquitectura | Fábrica de bloques · acabado mineral claro | block_masonry | [0.843137,0.823529,0.772549] | 0.96 | 0 | Bloque hueco documentado. Apariencia mineral clara para distinguir el cerramiento; no confirma un revoco ni su espesor. | Arquitectura; BIM · Arquitectura | El plano general de 2026-07-31 mantiene el edificio de oficinas de 200 m², mientras documentación anterior indica su supresión. Se conserva lo dibujado, pendiente de confirmación de la propiedad y del equipo de diseño.
Edificio de oficinas · Fábrica de bloques huecos de hormigón de 200 mm · eje B · tramo 56 | Planos de arquitectura del edificio de oficinas | Bloque hueco de hormigón de árido ligero | 0.8 × 0.2 × 1.2 | 287.05 | 288.25 | 0.192 | office_0178 | yes | 0.307099 | 0.819786 | 1.2 | 2.72 | 0.192 | office | Edificio de oficinas | {"name":"Bloque hueco de hormigón de árido ligero","source":"ARQ-OF-20260710 · Arquitectura A101 / p. 3, A103 / p. 5, A106 / p. 8; A301Cuadro de materiales ","status":"known"} | {"documented":[{"label":"Espesor del muro","value":0.2,"unit":"m","source":"ARQ-OF-20260710 · Arquitectura A101 / p. 3, A103 / p. 5, A106 / p. 8; A301Cuadro de materiales ","status":"documentado"}],"geometry":[{"label":"Dimensiones de la caja local del elemento (X, Y, Z)","value":"0.8 × 0.2 × 1.2","unit":"m","source":"Malla triangulada del elemento en ejes locales del edificio","status":"derivado"},{"label":"Cota mínima absoluta de la malla","value":287.05,"unit":"m","source":"Malla de proyecto y origen altimétrico 285 m","status":"derivado"},{"label":"Cota máxima absoluta de la malla","value":288.25,"unit":"m","source":"Malla de proyecto y origen altimétrico 285 m","status":"derivado"},{"label":"Volumen geométrico bruto","value":0.192,"unit":"m³","source":"Malla cerrada del elemento","status":"derivado"}],"notes":["Las dimensiones documentadas proceden de anotaciones o cuadros; la caja y el volumen se calculan a partir de la malla.","El volumen es exclusivamente geométrico y bruto; no representa una medición neta de material ni una cantidad de compra."]} | {"documentId":"ARQ-OF-20260710","title":"Planos de arquitectura del edificio de oficinas","date":"2026-07-10","sheet":"Arquitectura A101 / p. 3, A103 / p. 5, A106 / p. 8; A301Cuadro de materiales "} | ["El plano general de 2026-07-31 mantiene el edificio de oficinas de 200 m², mientras documentación anterior indica su supresión. Se conserva lo dibujado, pendiente de confirmación de la propiedad y del equipo de diseño.","Envolvente exterior controlada por la planta de arquitectura; no se han modelado individualmente todas las capas de acabado.","Registro de líneas del PDF general, envolvente de 20 × 10 m; eje local 1 al norte y acceso del lado A al oeste. Estimación de trabajo de implantación de ±0,15 m, pendiente de CAD; no constituye una precisión topográfica garantizada."] | {"horizontalStatus":"derivado","verticalStatus":"derivado","baseElevationM":285.95,"note":"Registro de líneas del PDF general, envolvente de 20 × 10 m; eje local 1 al norte y acceso del lado A al oeste. Estimación de trabajo de implantación de ±0,15 m, pendiente de CAD; no constituye una precisión topográfica garantizada."} | {"Pset_WallCommon":{"IsExternal":{"value":true,"source":"ARQ-OF-20260710 · A101, A103 y alzados; elemento de la envolvente exterior identificada en planta","status":"known"}}} | {"boundingBoxM":{"min":[24.527229,71.742172,2.05],"max":[24.834328,72.561958,3.25]},"extentsM":[0.307099,0.819786,1.2],"meshSurfaceM2":2.72,"meshVolumeM3":0.192,"closedSolid":true,"basis":"Geometría triangulada releída del IFC; envolventes y magnitudes no contractuales."} | {"material":true,"document":true,"quantities":true,"containerGuid":"3ztlotcerHPueDgxP84R6z","containerName":"Planta baja"} | {"id":"architecture","name":"Arquitectura"} | {"profileId":"block_masonry","name":"Fábrica de bloques · acabado mineral claro","materialName":"Bloque hueco de hormigón de árido ligero","physicalMaterialStatus":"known","physicalMaterialSource":"ARQ-OF-20260710 · Arquitectura A101 / p. 3, A103 / p. 5, A106 / p. 8; A301Cuadro de materiales ","appearanceStatus":"criterio_visual","appearanceBasis":"Bloque hueco documentado. Apariencia mineral clara para distinguir el cerramiento; no confirma un revoco ni su espesor.","note":"La apariencia gráfica no modifica ni confirma la especificación física del material."} | {"elementId":"office_0178","ifcGuid":"1rah_p5m1RxxHvX$Pp0Gjg","ifcClass":"IfcWall","buildingId":"office","buildingName":"Edificio de oficinas","sourceDocumentId":"ARQ-OF-20260710","sourceRepresentationKind":"documentary_mesh"} | {"layerId":"architecture","layerName":"Arquitectura","role":"Muro","basis":"Clasificación por función del elemento; no modifica las especificaciones documentales."} | architecture | {"profileId":"block_masonry","name":"Fábrica de bloques · acabado mineral claro","status":"criterio_visual","basis":"Bloque hueco documentado. Apariencia mineral clara para distinguir el cerramiento; no confirma un revoco ni su espesor.","physicalMaterialUnchanged":true} | ARQ-OF-20260710 · Arquitectura A101 / p. 3, A103 / p. 5, A106 / p. 8; A301Cuadro de materiales | Dimensiones contrastadas con los planos; reconstrucción geométrica a partir de documentación de diseño. | 0.2 | Muros segmentados con huecos reales para puertas y ventanas. | Envolvente exterior controlada por la planta de arquitectura; no se han modelado individualmente todas las capas de acabado. | Registro de líneas del PDF general, envolvente de 20 × 10 m; eje local 1 al norte y acceso del lado A al oeste. Estimación de trabajo de implantación de ±0,15 m, pendiente de CAD; no constituye una precisión topográfica garantizada. | Arquitectura | ARQ-OF-20260710 · Arquitectura A101 / p. 3, A103 / p. 5, A106 / p. 8; A301Cuadro de materiales | 285.95 | Arquitectura | Fábrica de bloques · acabado mineral claro | block_masonry | [0.843137,0.823529,0.772549] | 0.96 | 0 | Bloque hueco documentado. Apariencia mineral clara para distinguir el cerramiento; no confirma un revoco ni su espesor. | Arquitectura; BIM · Arquitectura | El plano general de 2026-07-31 mantiene el edificio de oficinas de 200 m², mientras documentación anterior indica su supresión. Se conserva lo dibujado, pendiente de confirmación de la propiedad y del equipo de diseño.
Edificio de oficinas · Fábrica de bloques huecos de hormigón de 200 mm · eje B · tramo 57 | Planos de arquitectura del edificio de oficinas | Bloque hueco de hormigón de árido ligero | 0.8 × 0.2 × 1.1 | 288.25 | 289.35 | 0.176 | office_0179 | yes | 0.307099 | 0.819786 | 1.1 | 2.52 | 0.176 | office | Edificio de oficinas | {"name":"Bloque hueco de hormigón de árido ligero","source":"ARQ-OF-20260710 · Arquitectura A101 / p. 3, A103 / p. 5, A106 / p. 8; A301Cuadro de materiales ","status":"known"} | {"documented":[{"label":"Espesor del muro","value":0.2,"unit":"m","source":"ARQ-OF-20260710 · Arquitectura A101 / p. 3, A103 / p. 5, A106 / p. 8; A301Cuadro de materiales ","status":"documentado"}],"geometry":[{"label":"Dimensiones de la caja local del elemento (X, Y, Z)","value":"0.8 × 0.2 × 1.1","unit":"m","source":"Malla triangulada del elemento en ejes locales del edificio","status":"derivado"},{"label":"Cota mínima absoluta de la malla","value":288.25,"unit":"m","source":"Malla de proyecto y origen altimétrico 285 m","status":"derivado"},{"label":"Cota máxima absoluta de la malla","value":289.35,"unit":"m","source":"Malla de proyecto y origen altimétrico 285 m","status":"derivado"},{"label":"Volumen geométrico bruto","value":0.176,"unit":"m³","source":"Malla cerrada del elemento","status":"derivado"}],"notes":["Las dimensiones documentadas proceden de anotaciones o cuadros; la caja y el volumen se calculan a partir de la malla.","El volumen es exclusivamente geométrico y bruto; no representa una medición neta de material ni una cantidad de compra."]} | {"documentId":"ARQ-OF-20260710","title":"Planos de arquitectura del edificio de oficinas","date":"2026-07-10","sheet":"Arquitectura A101 / p. 3, A103 / p. 5, A106 / p. 8; A301Cuadro de materiales "} | ["El plano general de 2026-07-31 mantiene el edificio de oficinas de 200 m², mientras documentación anterior indica su supresión. Se conserva lo dibujado, pendiente de confirmación de la propiedad y del equipo de diseño.","Envolvente exterior controlada por la planta de arquitectura; no se han modelado individualmente todas las capas de acabado.","Registro de líneas del PDF general, envolvente de 20 × 10 m; eje local 1 al norte y acceso del lado A al oeste. Estimación de trabajo de implantación de ±0,15 m, pendiente de CAD; no constituye una precisión topográfica garantizada."] | {"horizontalStatus":"derivado","verticalStatus":"derivado","baseElevationM":285.95,"note":"Registro de líneas del PDF general, envolvente de 20 × 10 m; eje local 1 al norte y acceso del lado A al oeste. Estimación de trabajo de implantación de ±0,15 m, pendiente de CAD; no constituye una precisión topográfica garantizada."} | {"Pset_WallCommon":{"IsExternal":{"value":true,"source":"ARQ-OF-20260710 · A101, A103 y alzados; elemento de la envolvente exterior identificada en planta","status":"known"}}} | {"boundingBoxM":{"min":[24.527229,71.742172,3.25],"max":[24.834328,72.561958,4.35]},"extentsM":[0.307099,0.819786,1.1],"meshSurfaceM2":2.52,"meshVolumeM3":0.176,"closedSolid":true,"basis":"Geometría triangulada releída del IFC; envolventes y magnitudes no contractuales."} | {"material":true,"document":true,"quantities":true,"containerGuid":"3ztlotcerHPueDgxP84R6z","containerName":"Planta baja"} | {"id":"architecture","name":"Arquitectura"} | {"profileId":"block_masonry","name":"Fábrica de bloques · acabado mineral claro","materialName":"Bloque hueco de hormigón de árido ligero","physicalMaterialStatus":"known","physicalMaterialSource":"ARQ-OF-20260710 · Arquitectura A101 / p. 3, A103 / p. 5, A106 / p. 8; A301Cuadro de materiales ","appearanceStatus":"criterio_visual","appearanceBasis":"Bloque hueco documentado. Apariencia mineral clara para distinguir el cerramiento; no confirma un revoco ni su espesor.","note":"La apariencia gráfica no modifica ni confirma la especificación física del material."} | {"elementId":"office_0179","ifcGuid":"2G_bOribvS2wbAD8Rv$5a9","ifcClass":"IfcWall","buildingId":"office","buildingName":"Edificio de oficinas","sourceDocumentId":"ARQ-OF-20260710","sourceRepresentationKind":"documentary_mesh"} | {"layerId":"architecture","layerName":"Arquitectura","role":"Muro","basis":"Clasificación por función del elemento; no modifica las especificaciones documentales."} | architecture | {"profileId":"block_masonry","name":"Fábrica de bloques · acabado mineral claro","status":"criterio_visual","basis":"Bloque hueco documentado. Apariencia mineral clara para distinguir el cerramiento; no confirma un revoco ni su espesor.","physicalMaterialUnchanged":true} | ARQ-OF-20260710 · Arquitectura A101 / p. 3, A103 / p. 5, A106 / p. 8; A301Cuadro de materiales | Dimensiones contrastadas con los planos; reconstrucción geométrica a partir de documentación de diseño. | 0.2 | Muros segmentados con huecos reales para puertas y ventanas. | Envolvente exterior controlada por la planta de arquitectura; no se han modelado individualmente todas las capas de acabado. | Registro de líneas del PDF general, envolvente de 20 × 10 m; eje local 1 al norte y acceso del lado A al oeste. Estimación de trabajo de implantación de ±0,15 m, pendiente de CAD; no constituye una precisión topográfica garantizada. | Arquitectura | ARQ-OF-20260710 · Arquitectura A101 / p. 3, A103 / p. 5, A106 / p. 8; A301Cuadro de materiales | 285.95 | Arquitectura | Fábrica de bloques · acabado mineral claro | block_masonry | [0.843137,0.823529,0.772549] | 0.96 | 0 | Bloque hueco documentado. Apariencia mineral clara para distinguir el cerramiento; no confirma un revoco ni su espesor. | Arquitectura; BIM · Arquitectura | El plano general de 2026-07-31 mantiene el edificio de oficinas de 200 m², mientras documentación anterior indica su supresión. Se conserva lo dibujado, pendiente de confirmación de la propiedad y del equipo de diseño.
Edificio de oficinas · Fábrica de bloques huecos de hormigón de 200 mm · eje B · tramo 58 | Planos de arquitectura del edificio de oficinas | Bloque hueco de hormigón de árido ligero | 0.8 × 0.2 × 1.6 | 289.35 | 290.95 | 0.256 | office_0180 | yes | 0.307099 | 0.819786 | 1.6 | 3.52 | 0.256 | office | Edificio de oficinas | {"name":"Bloque hueco de hormigón de árido ligero","source":"ARQ-OF-20260710 · Arquitectura A101 / p. 3, A103 / p. 5, A106 / p. 8; A301Cuadro de materiales ","status":"known"} | {"documented":[{"label":"Espesor del muro","value":0.2,"unit":"m","source":"ARQ-OF-20260710 · Arquitectura A101 / p. 3, A103 / p. 5, A106 / p. 8; A301Cuadro de materiales ","status":"documentado"}],"geometry":[{"label":"Dimensiones de la caja local del elemento (X, Y, Z)","value":"0.8 × 0.2 × 1.6","unit":"m","source":"Malla triangulada del elemento en ejes locales del edificio","status":"derivado"},{"label":"Cota mínima absoluta de la malla","value":289.35,"unit":"m","source":"Malla de proyecto y origen altimétrico 285 m","status":"derivado"},{"label":"Cota máxima absoluta de la malla","value":290.95,"unit":"m","source":"Malla de proyecto y origen altimétrico 285 m","status":"derivado"},{"label":"Volumen geométrico bruto","value":0.256,"unit":"m³","source":"Malla cerrada del elemento","status":"derivado"}],"notes":["Las dimensiones documentadas proceden de anotaciones o cuadros; la caja y el volumen se calculan a partir de la malla.","El volumen es exclusivamente geométrico y bruto; no representa una medición neta de material ni una cantidad de compra."]} | {"documentId":"ARQ-OF-20260710","title":"Planos de arquitectura del edificio de oficinas","date":"2026-07-10","sheet":"Arquitectura A101 / p. 3, A103 / p. 5, A106 / p. 8; A301Cuadro de materiales "} | ["El plano general de 2026-07-31 mantiene el edificio de oficinas de 200 m², mientras documentación anterior indica su supresión. Se conserva lo dibujado, pendiente de confirmación de la propiedad y del equipo de diseño.","Envolvente exterior controlada por la planta de arquitectura; no se han modelado individualmente todas las capas de acabado.","Registro de líneas del PDF general, envolvente de 20 × 10 m; eje local 1 al norte y acceso del lado A al oeste. Estimación de trabajo de implantación de ±0,15 m, pendiente de CAD; no constituye una precisión topográfica garantizada."] | {"horizontalStatus":"derivado","verticalStatus":"derivado","baseElevationM":285.95,"note":"Registro de líneas del PDF general, envolvente de 20 × 10 m; eje local 1 al norte y acceso del lado A al oeste. Estimación de trabajo de implantación de ±0,15 m, pendiente de CAD; no constituye una precisión topográfica garantizada."} | {"Pset_WallCommon":{"IsExternal":{"value":true,"source":"ARQ-OF-20260710 · A101, A103 y alzados; elemento de la envolvente exterior identificada en planta","status":"known"}}} | {"boundingBoxM":{"min":[24.527229,71.742172,4.35],"max":[24.834328,72.561958,5.95]},"extentsM":[0.307099,0.819786,1.6],"meshSurfaceM2":3.520001,"meshVolumeM3":0.256,"closedSolid":true,"basis":"Geometría triangulada releída del IFC; envolventes y magnitudes no contractuales."} | {"material":true,"document":true,"quantities":true,"containerGuid":"3ztlotcerHPueDgxP84R6z","containerName":"Planta baja"} | {"id":"architecture","name":"Arquitectura"} | {"profileId":"block_masonry","name":"Fábrica de bloques · acabado mineral claro","materialName":"Bloque hueco de hormigón de árido ligero","physicalMaterialStatus":"known","physicalMaterialSource":"ARQ-OF-20260710 · Arquitectura A101 / p. 3, A103 / p. 5, A106 / p. 8; A301Cuadro de materiales ","appearanceStatus":"criterio_visual","appearanceBasis":"Bloque hueco documentado. Apariencia mineral clara para distinguir el cerramiento; no confirma un revoco ni su espesor.","note":"La apariencia gráfica no modifica ni confirma la especificación física del material."} | {"elementId":"office_0180","ifcGuid":"3$A5DgrYvGtgEu3eMx6Mx3","ifcClass":"IfcWall","buildingId":"office","buildingName":"Edificio de oficinas","sourceDocumentId":"ARQ-OF-20260710","sourceRepresentationKind":"documentary_mesh"} | {"layerId":"architecture","layerName":"Arquitectura","role":"Muro","basis":"Clasificación por función del elemento; no modifica las especificaciones documentales."} | architecture | {"profileId":"block_masonry","name":"Fábrica de bloques · acabado mineral claro","status":"criterio_visual","basis":"Bloque hueco documentado. Apariencia mineral clara para distinguir el cerramiento; no confirma un revoco ni su espesor.","physicalMaterialUnchanged":true} | ARQ-OF-20260710 · Arquitectura A101 / p. 3, A103 / p. 5, A106 / p. 8; A301Cuadro de materiales | Dimensiones contrastadas con los planos; reconstrucción geométrica a partir de documentación de diseño. | 0.2 | Muros segmentados con huecos reales para puertas y ventanas. | Envolvente exterior controlada por la planta de arquitectura; no se han modelado individualmente todas las capas de acabado. | Registro de líneas del PDF general, envolvente de 20 × 10 m; eje local 1 al norte y acceso del lado A al oeste. Estimación de trabajo de implantación de ±0,15 m, pendiente de CAD; no constituye una precisión topográfica garantizada. | Arquitectura | ARQ-OF-20260710 · Arquitectura A101 / p. 3, A103 / p. 5, A106 / p. 8; A301Cuadro de materiales | 285.95 | Arquitectura | Fábrica de bloques · acabado mineral claro | block_masonry | [0.843137,0.823529,0.772549] | 0.96 | 0 | Bloque hueco documentado. Apariencia mineral clara para distinguir el cerramiento; no confirma un revoco ni su espesor. | Arquitectura; BIM · Arquitectura | El plano general de 2026-07-31 mantiene el edificio de oficinas de 200 m², mientras documentación anterior indica su supresión. Se conserva lo dibujado, pendiente de confirmación de la propiedad y del equipo de diseño.
Edificio de oficinas · Fábrica de bloques huecos de hormigón de 200 mm · eje 1 · tramo 01 | Planos de arquitectura del edificio de oficinas | Bloque hueco de hormigón de árido ligero | 0.2 × 4.8 × 1.1 | 285.95 | 287.05 | 1.056 | office_0181 | yes | 4.78251 | 0.851915 | 1.1 | 12.92 | 1.056 | office | Edificio de oficinas | {"name":"Bloque hueco de hormigón de árido ligero","source":"ARQ-OF-20260710 · Arquitectura A101 / p. 3, A103 / p. 5, A106 / p. 8; A301Cuadro de materiales ","status":"known"} | {"documented":[{"label":"Espesor del muro","value":0.2,"unit":"m","source":"ARQ-OF-20260710 · Arquitectura A101 / p. 3, A103 / p. 5, A106 / p. 8; A301Cuadro de materiales ","status":"documentado"}],"geometry":[{"label":"Dimensiones de la caja local del elemento (X, Y, Z)","value":"0.2 × 4.8 × 1.1","unit":"m","source":"Malla triangulada del elemento en ejes locales del edificio","status":"derivado"},{"label":"Cota mínima absoluta de la malla","value":285.95,"unit":"m","source":"Malla de proyecto y origen altimétrico 285 m","status":"derivado"},{"label":"Cota máxima absoluta de la malla","value":287.05,"unit":"m","source":"Malla de proyecto y origen altimétrico 285 m","status":"derivado"},{"label":"Volumen geométrico bruto","value":1.056,"unit":"m³","source":"Malla cerrada del elemento","status":"derivado"}],"notes":["Las dimensiones documentadas proceden de anotaciones o cuadros; la caja y el volumen se calculan a partir de la malla.","El volumen es exclusivamente geométrico y bruto; no representa una medición neta de material ni una cantidad de compra."]} | {"documentId":"ARQ-OF-20260710","title":"Planos de arquitectura del edificio de oficinas","date":"2026-07-10","sheet":"Arquitectura A101 / p. 3, A103 / p. 5, A106 / p. 8; A301Cuadro de materiales "} | ["El plano general de 2026-07-31 mantiene el edificio de oficinas de 200 m², mientras documentación anterior indica su supresión. Se conserva lo dibujado, pendiente de confirmación de la propiedad y del equipo de diseño.","Envolvente exterior controlada por la planta de arquitectura; no se han modelado individualmente todas las capas de acabado.","Registro de líneas del PDF general, envolvente de 20 × 10 m; eje local 1 al norte y acceso del lado A al oeste. Estimación de trabajo de implantación de ±0,15 m, pendiente de CAD; no constituye una precisión topográfica garantizada."] | {"horizontalStatus":"derivado","verticalStatus":"derivado","baseElevationM":285.95,"note":"Registro de líneas del PDF general, envolvente de 20 × 10 m; eje local 1 al norte y acceso del lado A al oeste. Estimación de trabajo de implantación de ±0,15 m, pendiente de CAD; no constituye una precisión topográfica garantizada."} | {"Pset_WallCommon":{"IsExternal":{"value":true,"source":"ARQ-OF-20260710 · A101, A103 y alzados; elemento de la envolvente exterior identificada en planta","status":"known"}}} | {"boundingBoxM":{"min":[17.713531,92.038672,0.95],"max":[22.496039,92.890587,2.05]},"extentsM":[4.782508,0.851915,1.1],"meshSurfaceM2":12.919997,"meshVolumeM3":1.055999,"closedSolid":true,"basis":"Geometría triangulada releída del IFC; envolventes y magnitudes no contractuales."} | {"material":true,"document":true,"quantities":true,"containerGuid":"3ztlotcerHPueDgxP84R6z","containerName":"Planta baja"} | {"id":"architecture","name":"Arquitectura"} | {"profileId":"block_masonry","name":"Fábrica de bloques · acabado mineral claro","materialName":"Bloque hueco de hormigón de árido ligero","physicalMaterialStatus":"known","physicalMaterialSource":"ARQ-OF-20260710 · Arquitectura A101 / p. 3, A103 / p. 5, A106 / p. 8; A301Cuadro de materiales ","appearanceStatus":"criterio_visual","appearanceBasis":"Bloque hueco documentado. Apariencia mineral clara para distinguir el cerramiento; no confirma un revoco ni su espesor.","note":"La apariencia gráfica no modifica ni confirma la especificación física del material."} | {"elementId":"office_0181","ifcGuid":"08miazt31SwwTIkO_YRckS","ifcClass":"IfcWall","buildingId":"office","buildingName":"Edificio de oficinas","sourceDocumentId":"ARQ-OF-20260710","sourceRepresentationKind":"documentary_mesh"} | {"layerId":"architecture","layerName":"Arquitectura","role":"Muro","basis":"Clasificación por función del elemento; no modifica las especificaciones documentales."} | architecture | {"profileId":"block_masonry","name":"Fábrica de bloques · acabado mineral claro","status":"criterio_visual","basis":"Bloque hueco documentado. Apariencia mineral clara para distinguir el cerramiento; no confirma un revoco ni su espesor.","physicalMaterialUnchanged":true} | ARQ-OF-20260710 · Arquitectura A101 / p. 3, A103 / p. 5, A106 / p. 8; A301Cuadro de materiales | Dimensiones contrastadas con los planos; reconstrucción geométrica a partir de documentación de diseño. | 0.2 | Muros segmentados con huecos reales para puertas y ventanas. | Envolvente exterior controlada por la planta de arquitectura; no se han modelado individualmente todas las capas de acabado. | Registro de líneas del PDF general, envolvente de 20 × 10 m; eje local 1 al norte y acceso del lado A al oeste. Estimación de trabajo de implantación de ±0,15 m, pendiente de CAD; no constituye una precisión topográfica garantizada. | Arquitectura | ARQ-OF-20260710 · Arquitectura A101 / p. 3, A103 / p. 5, A106 / p. 8; A301Cuadro de materiales | 285.95 | Arquitectura | Fábrica de bloques · acabado mineral claro | block_masonry | [0.843137,0.823529,0.772549] | 0.96 | 0 | Bloque hueco documentado. Apariencia mineral clara para distinguir el cerramiento; no confirma un revoco ni su espesor. | Arquitectura; BIM · Arquitectura | El plano general de 2026-07-31 mantiene el edificio de oficinas de 200 m², mientras documentación anterior indica su supresión. Se conserva lo dibujado, pendiente de confirmación de la propiedad y del equipo de diseño.
Edificio de oficinas · Fábrica de bloques huecos de hormigón de 200 mm · eje 1 · tramo 02 | Planos de arquitectura del edificio de oficinas | Bloque hueco de hormigón de árido ligero | 0.2 × 4.8 × 2.3 | 287.05 | 289.35 | 2.208 | office_0182 | yes | 4.78251 | 0.851915 | 2.3 | 24.92 | 2.208 | office | Edificio de oficinas | {"name":"Bloque hueco de hormigón de árido ligero","source":"ARQ-OF-20260710 · Arquitectura A101 / p. 3, A103 / p. 5, A106 / p. 8; A301Cuadro de materiales ","status":"known"} | {"documented":[{"label":"Espesor del muro","value":0.2,"unit":"m","source":"ARQ-OF-20260710 · Arquitectura A101 / p. 3, A103 / p. 5, A106 / p. 8; A301Cuadro de materiales ","status":"documentado"}],"geometry":[{"label":"Dimensiones de la caja local del elemento (X, Y, Z)","value":"0.2 × 4.8 × 2.3","unit":"m","source":"Malla triangulada del elemento en ejes locales del edificio","status":"derivado"},{"label":"Cota mínima absoluta de la malla","value":287.05,"unit":"m","source":"Malla de proyecto y origen altimétrico 285 m","status":"derivado"},{"label":"Cota máxima absoluta de la malla","value":289.35,"unit":"m","source":"Malla de proyecto y origen altimétrico 285 m","status":"derivado"},{"label":"Volumen geométrico bruto","value":2.208,"unit":"m³","source":"Malla cerrada del elemento","status":"derivado"}],"notes":["Las dimensiones documentadas proceden de anotaciones o cuadros; la caja y el volumen se calculan a partir de la malla.","El volumen es exclusivamente geométrico y bruto; no representa una medición neta de material ni una cantidad de compra."]} | {"documentId":"ARQ-OF-20260710","title":"Planos de arquitectura del edificio de oficinas","date":"2026-07-10","sheet":"Arquitectura A101 / p. 3, A103 / p. 5, A106 / p. 8; A301Cuadro de materiales "} | ["El plano general de 2026-07-31 mantiene el edificio de oficinas de 200 m², mientras documentación anterior indica su supresión. Se conserva lo dibujado, pendiente de confirmación de la propiedad y del equipo de diseño.","Envolvente exterior controlada por la planta de arquitectura; no se han modelado individualmente todas las capas de acabado.","Registro de líneas del PDF general, envolvente de 20 × 10 m; eje local 1 al norte y acceso del lado A al oeste. Estimación de trabajo de implantación de ±0,15 m, pendiente de CAD; no constituye una precisión topográfica garantizada."] | {"horizontalStatus":"derivado","verticalStatus":"derivado","baseElevationM":285.95,"note":"Registro de líneas del PDF general, envolvente de 20 × 10 m; eje local 1 al norte y acceso del lado A al oeste. Estimación de trabajo de implantación de ±0,15 m, pendiente de CAD; no constituye una precisión topográfica garantizada."} | {"Pset_WallCommon":{"IsExternal":{"value":true,"source":"ARQ-OF-20260710 · A101, A103 y alzados; elemento de la envolvente exterior identificada en planta","status":"known"}}} | {"boundingBoxM":{"min":[17.713531,92.038672,2.05],"max":[22.496039,92.890587,4.35]},"extentsM":[4.782508,0.851915,2.3],"meshSurfaceM2":24.919995,"meshVolumeM3":2.207998,"closedSolid":true,"basis":"Geometría triangulada releída del IFC; envolventes y magnitudes no contractuales."} | {"material":true,"document":true,"quantities":true,"containerGuid":"3ztlotcerHPueDgxP84R6z","containerName":"Planta baja"} | {"id":"architecture","name":"Arquitectura"} | {"profileId":"block_masonry","name":"Fábrica de bloques · acabado mineral claro","materialName":"Bloque hueco de hormigón de árido ligero","physicalMaterialStatus":"known","physicalMaterialSource":"ARQ-OF-20260710 · Arquitectura A101 / p. 3, A103 / p. 5, A106 / p. 8; A301Cuadro de materiales ","appearanceStatus":"criterio_visual","appearanceBasis":"Bloque hueco documentado. Apariencia mineral clara para distinguir el cerramiento; no confirma un revoco ni su espesor.","note":"La apariencia gráfica no modifica ni confirma la especificación física del material."} | {"elementId":"office_0182","ifcGuid":"1oayoBda9Vhu80AyJ96NMS","ifcClass":"IfcWall","buildingId":"office","buildingName":"Edificio de oficinas","sourceDocumentId":"ARQ-OF-20260710","sourceRepresentationKind":"documentary_mesh"} | {"layerId":"architecture","layerName":"Arquitectura","role":"Muro","basis":"Clasificación por función del elemento; no modifica las especificaciones documentales."} | architecture | {"profileId":"block_masonry","name":"Fábrica de bloques · acabado mineral claro","status":"criterio_visual","basis":"Bloque hueco documentado. Apariencia mineral clara para distinguir el cerramiento; no confirma un revoco ni su espesor.","physicalMaterialUnchanged":true} | ARQ-OF-20260710 · Arquitectura A101 / p. 3, A103 / p. 5, A106 / p. 8; A301Cuadro de materiales | Dimensiones contrastadas con los planos; reconstrucción geométrica a partir de documentación de diseño. | 0.2 | Muros segmentados con huecos reales para puertas y ventanas. | Envolvente exterior controlada por la planta de arquitectura; no se han modelado individualmente todas las capas de acabado. | Registro de líneas del PDF general, envolvente de 20 × 10 m; eje local 1 al norte y acceso del lado A al oeste. Estimación de trabajo de implantación de ±0,15 m, pendiente de CAD; no constituye una precisión topográfica garantizada. | Arquitectura | ARQ-OF-20260710 · Arquitectura A101 / p. 3, A103 / p. 5, A106 / p. 8; A301Cuadro de materiales | 285.95 | Arquitectura | Fábrica de bloques · acabado mineral claro | block_masonry | [0.843137,0.823529,0.772549] | 0.96 | 0 | Bloque hueco documentado. Apariencia mineral clara para distinguir el cerramiento; no confirma un revoco ni su espesor. | Arquitectura; BIM · Arquitectura | El plano general de 2026-07-31 mantiene el edificio de oficinas de 200 m², mientras documentación anterior indica su supresión. Se conserva lo dibujado, pendiente de confirmación de la propiedad y del equipo de diseño.
Edificio de oficinas · Fábrica de bloques huecos de hormigón de 200 mm · eje 1 · tramo 03 | Planos de arquitectura del edificio de oficinas | Bloque hueco de hormigón de árido ligero | 0.2 × 4.8 × 1.6 | 289.35 | 290.95 | 1.536 | office_0183 | yes | 4.78251 | 0.851915 | 1.6 | 17.92 | 1.536 | office | Edificio de oficinas | {"name":"Bloque hueco de hormigón de árido ligero","source":"ARQ-OF-20260710 · Arquitectura A101 / p. 3, A103 / p. 5, A106 / p. 8; A301Cuadro de materiales ","status":"known"} | {"documented":[{"label":"Espesor del muro","value":0.2,"unit":"m","source":"ARQ-OF-20260710 · Arquitectura A101 / p. 3, A103 / p. 5, A106 / p. 8; A301Cuadro de materiales ","status":"documentado"}],"geometry":[{"label":"Dimensiones de la caja local del elemento (X, Y, Z)","value":"0.2 × 4.8 × 1.6","unit":"m","source":"Malla triangulada del elemento en ejes locales del edificio","status":"derivado"},{"label":"Cota mínima absoluta de la malla","value":289.35,"unit":"m","source":"Malla de proyecto y origen altimétrico 285 m","status":"derivado"},{"label":"Cota máxima absoluta de la malla","value":290.95,"unit":"m","source":"Malla de proyecto y origen altimétrico 285 m","status":"derivado"},{"label":"Volumen geométrico bruto","value":1.536,"unit":"m³","source":"Malla cerrada del elemento","status":"derivado"}],"notes":["Las dimensiones documentadas proceden de anotaciones o cuadros; la caja y el volumen se calculan a partir de la malla.","El volumen es exclusivamente geométrico y bruto; no representa una medición neta de material ni una cantidad de compra."]} | {"documentId":"ARQ-OF-20260710","title":"Planos de arquitectura del edificio de oficinas","date":"2026-07-10","sheet":"Arquitectura A101 / p. 3, A103 / p. 5, A106 / p. 8; A301Cuadro de materiales "} | ["El plano general de 2026-07-31 mantiene el edificio de oficinas de 200 m², mientras documentación anterior indica su supresión. Se conserva lo dibujado, pendiente de confirmación de la propiedad y del equipo de diseño.","Envolvente exterior controlada por la planta de arquitectura; no se han modelado individualmente todas las capas de acabado.","Registro de líneas del PDF general, envolvente de 20 × 10 m; eje local 1 al norte y acceso del lado A al oeste. Estimación de trabajo de implantación de ±0,15 m, pendiente de CAD; no constituye una precisión topográfica garantizada."] | {"horizontalStatus":"derivado","verticalStatus":"derivado","baseElevationM":285.95,"note":"Registro de líneas del PDF general, envolvente de 20 × 10 m; eje local 1 al norte y acceso del lado A al oeste. Estimación de trabajo de implantación de ±0,15 m, pendiente de CAD; no constituye una precisión topográfica garantizada."} | {"Pset_WallCommon":{"IsExternal":{"value":true,"source":"ARQ-OF-20260710 · A101, A103 y alzados; elemento de la envolvente exterior identificada en planta","status":"known"}}} | {"boundingBoxM":{"min":[17.713531,92.038672,4.35],"max":[22.496039,92.890587,5.95]},"extentsM":[4.782508,0.851915,1.6],"meshSurfaceM2":17.919996,"meshVolumeM3":1.535998,"closedSolid":true,"basis":"Geometría triangulada releída del IFC; envolventes y magnitudes no contractuales."} | {"material":true,"document":true,"quantities":true,"containerGuid":"3ztlotcerHPueDgxP84R6z","containerName":"Planta baja"} | {"id":"architecture","name":"Arquitectura"} | {"profileId":"block_masonry","name":"Fábrica de bloques · acabado mineral claro","materialName":"Bloque hueco de hormigón de árido ligero","physicalMaterialStatus":"known","physicalMaterialSource":"ARQ-OF-20260710 · Arquitectura A101 / p. 3, A103 / p. 5, A106 / p. 8; A301Cuadro de materiales ","appearanceStatus":"criterio_visual","appearanceBasis":"Bloque hueco documentado. Apariencia mineral clara para distinguir el cerramiento; no confirma un revoco ni su espesor.","note":"La apariencia gráfica no modifica ni confirma la especificación física del material."} | {"elementId":"office_0183","ifcGuid":"363AUDS4rTGhY8_oP1UZ1O","ifcClass":"IfcWall","buildingId":"office","buildingName":"Edificio de oficinas","sourceDocumentId":"ARQ-OF-20260710","sourceRepresentationKind":"documentary_mesh"} | {"layerId":"architecture","layerName":"Arquitectura","role":"Muro","basis":"Clasificación por función del elemento; no modifica las especificaciones documentales."} | architecture | {"profileId":"block_masonry","name":"Fábrica de bloques · acabado mineral claro","status":"criterio_visual","basis":"Bloque hueco documentado. Apariencia mineral clara para distinguir el cerramiento; no confirma un revoco ni su espesor.","physicalMaterialUnchanged":true} | ARQ-OF-20260710 · Arquitectura A101 / p. 3, A103 / p. 5, A106 / p. 8; A301Cuadro de materiales | Dimensiones contrastadas con los planos; reconstrucción geométrica a partir de documentación de diseño. | 0.2 | Muros segmentados con huecos reales para puertas y ventanas. | Envolvente exterior controlada por la planta de arquitectura; no se han modelado individualmente todas las capas de acabado. | Registro de líneas del PDF general, envolvente de 20 × 10 m; eje local 1 al norte y acceso del lado A al oeste. Estimación de trabajo de implantación de ±0,15 m, pendiente de CAD; no constituye una precisión topográfica garantizada. | Arquitectura | ARQ-OF-20260710 · Arquitectura A101 / p. 3, A103 / p. 5, A106 / p. 8; A301Cuadro de materiales | 285.95 | Arquitectura | Fábrica de bloques · acabado mineral claro | block_masonry | [0.843137,0.823529,0.772549] | 0.96 | 0 | Bloque hueco documentado. Apariencia mineral clara para distinguir el cerramiento; no confirma un revoco ni su espesor. | Arquitectura; BIM · Arquitectura | El plano general de 2026-07-31 mantiene el edificio de oficinas de 200 m², mientras documentación anterior indica su supresión. Se conserva lo dibujado, pendiente de confirmación de la propiedad y del equipo de diseño.
Edificio de oficinas · Fábrica de bloques huecos de hormigón de 200 mm · eje 1 · tramo 04 | Planos de arquitectura del edificio de oficinas | Bloque hueco de hormigón de árido ligero | 0.2 × 0.9 × 1.1 | 285.95 | 287.05 | 0.198 | office_0184 | yes | 0.918854 | 0.320719 | 1.1 | 2.78 | 0.198 | office | Edificio de oficinas | {"name":"Bloque hueco de hormigón de árido ligero","source":"ARQ-OF-20260710 · Arquitectura A101 / p. 3, A103 / p. 5, A106 / p. 8; A301Cuadro de materiales ","status":"known"} | {"documented":[{"label":"Espesor del muro","value":0.2,"unit":"m","source":"ARQ-OF-20260710 · Arquitectura A101 / p. 3, A103 / p. 5, A106 / p. 8; A301Cuadro de materiales ","status":"documentado"}],"geometry":[{"label":"Dimensiones de la caja local del elemento (X, Y, Z)","value":"0.2 × 0.9 × 1.1","unit":"m","source":"Malla triangulada del elemento en ejes locales del edificio","status":"derivado"},{"label":"Cota mínima absoluta de la malla","value":285.95,"unit":"m","source":"Malla de proyecto y origen altimétrico 285 m","status":"derivado"},{"label":"Cota máxima absoluta de la malla","value":287.05,"unit":"m","source":"Malla de proyecto y origen altimétrico 285 m","status":"derivado"},{"label":"Volumen geométrico bruto","value":0.198,"unit":"m³","source":"Malla cerrada del elemento","status":"derivado"}],"notes":["Las dimensiones documentadas proceden de anotaciones o cuadros; la caja y el volumen se calculan a partir de la malla.","El volumen es exclusivamente geométrico y bruto; no representa una medición neta de material ni una cantidad de compra."]} | {"documentId":"ARQ-OF-20260710","title":"Planos de arquitectura del edificio de oficinas","date":"2026-07-10","sheet":"Arquitectura A101 / p. 3, A103 / p. 5, A106 / p. 8; A301Cuadro de materiales "} | ["El plano general de 2026-07-31 mantiene el edificio de oficinas de 200 m², mientras documentación anterior indica su supresión. Se conserva lo dibujado, pendiente de confirmación de la propiedad y del equipo de diseño.","Envolvente exterior controlada por la planta de arquitectura; no se han modelado individualmente todas las capas de acabado.","Registro de líneas del PDF general, envolvente de 20 × 10 m; eje local 1 al norte y acceso del lado A al oeste. Estimación de trabajo de implantación de ±0,15 m, pendiente de CAD; no constituye una precisión topográfica garantizada."] | {"horizontalStatus":"derivado","verticalStatus":"derivado","baseElevationM":285.95,"note":"Registro de líneas del PDF general, envolvente de 20 × 10 m; eje local 1 al norte y acceso del lado A al oeste. Estimación de trabajo de implantación de ±0,15 m, pendiente de CAD; no constituye una precisión topográfica garantizada."} | {"Pset_WallCommon":{"IsExternal":{"value":true,"source":"ARQ-OF-20260710 · A101, A103 y alzados; elemento de la envolvente exterior identificada en planta","status":"known"}}} | {"boundingBoxM":{"min":[22.468798,91.916089,0.95],"max":[23.387652,92.236808,2.05]},"extentsM":[0.918854,0.320719,1.1],"meshSurfaceM2":2.78,"meshVolumeM3":0.198,"closedSolid":true,"basis":"Geometría triangulada releída del IFC; envolventes y magnitudes no contractuales."} | {"material":true,"document":true,"quantities":true,"containerGuid":"3ztlotcerHPueDgxP84R6z","containerName":"Planta baja"} | {"id":"architecture","name":"Arquitectura"} | {"profileId":"block_masonry","name":"Fábrica de bloques · acabado mineral claro","materialName":"Bloque hueco de hormigón de árido ligero","physicalMaterialStatus":"known","physicalMaterialSource":"ARQ-OF-20260710 · Arquitectura A101 / p. 3, A103 / p. 5, A106 / p. 8; A301Cuadro de materiales ","appearanceStatus":"criterio_visual","appearanceBasis":"Bloque hueco documentado. Apariencia mineral clara para distinguir el cerramiento; no confirma un revoco ni su espesor.","note":"La apariencia gráfica no modifica ni confirma la especificación física del material."} | {"elementId":"office_0184","ifcGuid":"0gkUq509POdeIU_pI_KY3V","ifcClass":"IfcWall","buildingId":"office","buildingName":"Edificio de oficinas","sourceDocumentId":"ARQ-OF-20260710","sourceRepresentationKind":"documentary_mesh"} | {"layerId":"architecture","layerName":"Arquitectura","role":"Muro","basis":"Clasificación por función del elemento; no modifica las especificaciones documentales."} | architecture | {"profileId":"block_masonry","name":"Fábrica de bloques · acabado mineral claro","status":"criterio_visual","basis":"Bloque hueco documentado. Apariencia mineral clara para distinguir el cerramiento; no confirma un revoco ni su espesor.","physicalMaterialUnchanged":true} | ARQ-OF-20260710 · Arquitectura A101 / p. 3, A103 / p. 5, A106 / p. 8; A301Cuadro de materiales | Dimensiones contrastadas con los planos; reconstrucción geométrica a partir de documentación de diseño. | 0.2 | Muros segmentados con huecos reales para puertas y ventanas. | Envolvente exterior controlada por la planta de arquitectura; no se han modelado individualmente todas las capas de acabado. | Registro de líneas del PDF general, envolvente de 20 × 10 m; eje local 1 al norte y acceso del lado A al oeste. Estimación de trabajo de implantación de ±0,15 m, pendiente de CAD; no constituye una precisión topográfica garantizada. | Arquitectura | ARQ-OF-20260710 · Arquitectura A101 / p. 3, A103 / p. 5, A106 / p. 8; A301Cuadro de materiales | 285.95 | Arquitectura | Fábrica de bloques · acabado mineral claro | block_masonry | [0.843137,0.823529,0.772549] | 0.96 | 0 | Bloque hueco documentado. Apariencia mineral clara para distinguir el cerramiento; no confirma un revoco ni su espesor. | Arquitectura; BIM · Arquitectura | El plano general de 2026-07-31 mantiene el edificio de oficinas de 200 m², mientras documentación anterior indica su supresión. Se conserva lo dibujado, pendiente de confirmación de la propiedad y del equipo de diseño.
Edificio de oficinas · Fábrica de bloques huecos de hormigón de 200 mm · eje 1 · tramo 05 | Planos de arquitectura del edificio de oficinas | Bloque hueco de hormigón de árido ligero | 0.2 × 0.9 × 1.6 | 289.35 | 290.95 | 0.288 | office_0185 | yes | 0.918854 | 0.320719 | 1.6 | 3.88 | 0.288 | office | Edificio de oficinas | {"name":"Bloque hueco de hormigón de árido ligero","source":"ARQ-OF-20260710 · Arquitectura A101 / p. 3, A103 / p. 5, A106 / p. 8; A301Cuadro de materiales ","status":"known"} | {"documented":[{"label":"Espesor del muro","value":0.2,"unit":"m","source":"ARQ-OF-20260710 · Arquitectura A101 / p. 3, A103 / p. 5, A106 / p. 8; A301Cuadro de materiales ","status":"documentado"}],"geometry":[{"label":"Dimensiones de la caja local del elemento (X, Y, Z)","value":"0.2 × 0.9 × 1.6","unit":"m","source":"Malla triangulada del elemento en ejes locales del edificio","status":"derivado"},{"label":"Cota mínima absoluta de la malla","value":289.35,"unit":"m","source":"Malla de proyecto y origen altimétrico 285 m","status":"derivado"},{"label":"Cota máxima absoluta de la malla","value":290.95,"unit":"m","source":"Malla de proyecto y origen altimétrico 285 m","status":"derivado"},{"label":"Volumen geométrico bruto","value":0.288,"unit":"m³","source":"Malla cerrada del elemento","status":"derivado"}],"notes":["Las dimensiones documentadas proceden de anotaciones o cuadros; la caja y el volumen se calculan a partir de la malla.","El volumen es exclusivamente geométrico y bruto; no representa una medición neta de material ni una cantidad de compra."]} | {"documentId":"ARQ-OF-20260710","title":"Planos de arquitectura del edificio de oficinas","date":"2026-07-10","sheet":"Arquitectura A101 / p. 3, A103 / p. 5, A106 / p. 8; A301Cuadro de materiales "} | ["El plano general de 2026-07-31 mantiene el edificio de oficinas de 200 m², mientras documentación anterior indica su supresión. Se conserva lo dibujado, pendiente de confirmación de la propiedad y del equipo de diseño.","Envolvente exterior controlada por la planta de arquitectura; no se han modelado individualmente todas las capas de acabado.","Registro de líneas del PDF general, envolvente de 20 × 10 m; eje local 1 al norte y acceso del lado A al oeste. Estimación de trabajo de implantación de ±0,15 m, pendiente de CAD; no constituye una precisión topográfica garantizada."] | {"horizontalStatus":"derivado","verticalStatus":"derivado","baseElevationM":285.95,"note":"Registro de líneas del PDF general, envolvente de 20 × 10 m; eje local 1 al norte y acceso del lado A al oeste. Estimación de trabajo de implantación de ±0,15 m, pendiente de CAD; no constituye una precisión topográfica garantizada."} | {"Pset_WallCommon":{"IsExternal":{"value":true,"source":"ARQ-OF-20260710 · A101, A103 y alzados; elemento de la envolvente exterior identificada en planta","status":"known"}}} | {"boundingBoxM":{"min":[22.468798,91.916089,4.35],"max":[23.387652,92.236808,5.95]},"extentsM":[0.918854,0.320719,1.6],"meshSurfaceM2":3.88,"meshVolumeM3":0.288,"closedSolid":true,"basis":"Geometría triangulada releída del IFC; envolventes y magnitudes no contractuales."} | {"material":true,"document":true,"quantities":true,"containerGuid":"3ztlotcerHPueDgxP84R6z","containerName":"Planta baja"} | {"id":"architecture","name":"Arquitectura"} | {"profileId":"block_masonry","name":"Fábrica de bloques · acabado mineral claro","materialName":"Bloque hueco de hormigón de árido ligero","physicalMaterialStatus":"known","physicalMaterialSource":"ARQ-OF-20260710 · Arquitectura A101 / p. 3, A103 / p. 5, A106 / p. 8; A301Cuadro de materiales ","appearanceStatus":"criterio_visual","appearanceBasis":"Bloque hueco documentado. Apariencia mineral clara para distinguir el cerramiento; no confirma un revoco ni su espesor.","note":"La apariencia gráfica no modifica ni confirma la especificación física del material."} | {"elementId":"office_0185","ifcGuid":"1I7iXAwarSAv3dAG5lregs","ifcClass":"IfcWall","buildingId":"office","buildingName":"Edificio de oficinas","sourceDocumentId":"ARQ-OF-20260710","sourceRepresentationKind":"documentary_mesh"} | {"layerId":"architecture","layerName":"Arquitectura","role":"Muro","basis":"Clasificación por función del elemento; no modifica las especificaciones documentales."} | architecture | {"profileId":"block_masonry","name":"Fábrica de bloques · acabado mineral claro","status":"criterio_visual","basis":"Bloque hueco documentado. Apariencia mineral clara para distinguir el cerramiento; no confirma un revoco ni su espesor.","physicalMaterialUnchanged":true} | ARQ-OF-20260710 · Arquitectura A101 / p. 3, A103 / p. 5, A106 / p. 8; A301Cuadro de materiales | Dimensiones contrastadas con los planos; reconstrucción geométrica a partir de documentación de diseño. | 0.2 | Muros segmentados con huecos reales para puertas y ventanas. | Envolvente exterior controlada por la planta de arquitectura; no se han modelado individualmente todas las capas de acabado. | Registro de líneas del PDF general, envolvente de 20 × 10 m; eje local 1 al norte y acceso del lado A al oeste. Estimación de trabajo de implantación de ±0,15 m, pendiente de CAD; no constituye una precisión topográfica garantizada. | Arquitectura | ARQ-OF-20260710 · Arquitectura A101 / p. 3, A103 / p. 5, A106 / p. 8; A301Cuadro de materiales | 285.95 | Arquitectura | Fábrica de bloques · acabado mineral claro | block_masonry | [0.843137,0.823529,0.772549] | 0.96 | 0 | Bloque hueco documentado. Apariencia mineral clara para distinguir el cerramiento; no confirma un revoco ni su espesor. | Arquitectura; BIM · Arquitectura | El plano general de 2026-07-31 mantiene el edificio de oficinas de 200 m², mientras documentación anterior indica su supresión. Se conserva lo dibujado, pendiente de confirmación de la propiedad y del equipo de diseño.
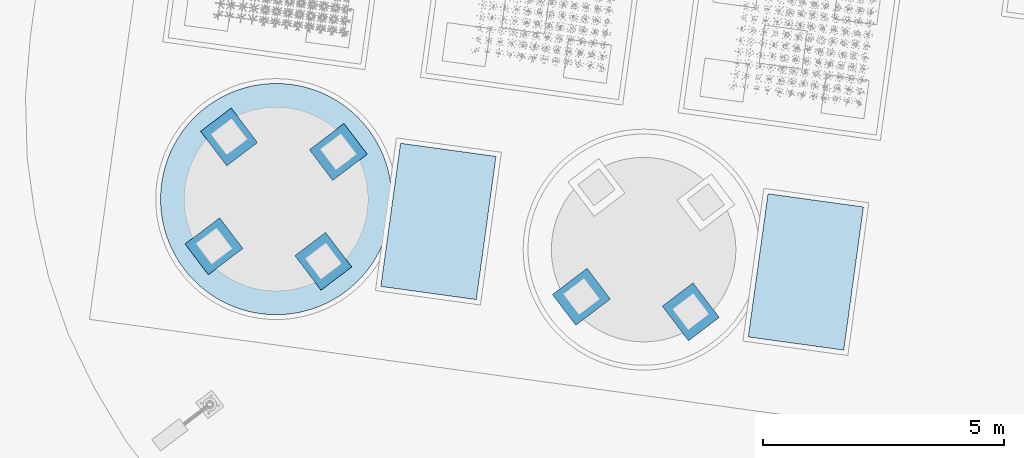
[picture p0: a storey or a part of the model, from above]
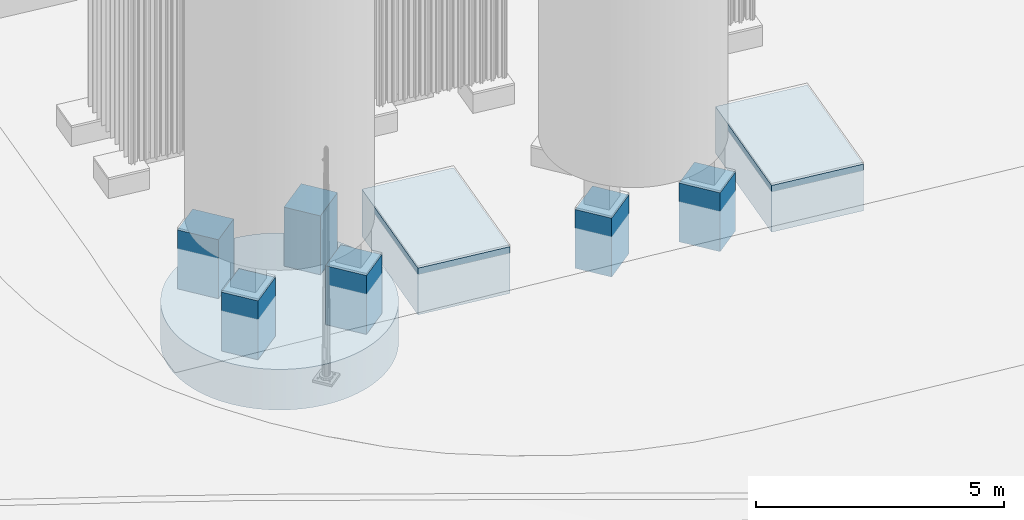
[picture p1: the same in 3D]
Properties of the parts of a building model (IFC4), part 130 of 134

# IfcWall (187)
Name | Document | Material = JH_Trazabilidad, Material = name | Dimensiones de la caja local del elemento (X, Y, Z) | Cota mínima absoluta de la malla (m) | Cota máxima absoluta de la malla (m) | Volumen geométrico bruto (m3) = Volumen geométrico (m³) | Reference = Identificador del elemento = Identificador | IsExternal | ExtensionX (m) | ExtensionY (m) | ExtensionZ (m) | SuperficieDeLaMalla (m2) | VolumenGeometrico (m3) = GrossVolume (m3) | buildingId | buildingName = Edificio | material | dimensions | JH_InformacionBIM, source = DocumentoFuente | issues = IncidenciasPendientes | positioning = PosicionYEstado | commonProperties | geometryMetrics | ifcAssociations | visualLayer | materialAppearance | visualizationIdentity | classification | layerId = IdentificadorCapa | appearance | Planos de referencia | Base geométrica | Espesor del muro (m) = Espesor del muro (m) | Tratamiento de los huecos | Representación de los acabados | Estado de la implantación | Disciplina | Referencia del material = JH_EvidenciaDeMaterial, source | Cota de planta baja terminada (m) | Capa BIM = NombreCapa | Acabado de visualización = Acabado | Perfil | ColorRGB | Rugosidad | Metallicidad | Referencia | Group | Discrepancia entre versiones
Edificio de oficinas · Fábrica de bloques huecos de hormigón de 200 mm · eje 3 · tramo 03 | Planos de arquitectura del edificio de oficinas | Bloque hueco de hormigón de árido ligero | 0.2 × 2.1 × 1.6 | 289.35 | 290.95 | 0.672 | office_0196 | yes | 2.10767 | 0.484165 | 1.6 | 8.2 | 0.672001 | office | Edificio de oficinas | {"name":"Bloque hueco de hormigón de árido ligero","source":"ARQ-OF-20260710 · Arquitectura A101 / p. 3, A103 / p. 5, A106 / p. 8; A301Cuadro de materiales ","status":"known"} | {"documented":[{"label":"Espesor del muro","value":0.2,"unit":"m","source":"ARQ-OF-20260710 · Arquitectura A101 / p. 3, A103 / p. 5, A106 / p. 8; A301Cuadro de materiales ","status":"documentado"}],"geometry":[{"label":"Dimensiones de la caja local del elemento (X, Y, Z)","value":"0.2 × 2.1 × 1.6","unit":"m","source":"Malla triangulada del elemento en ejes locales del edificio","status":"derivado"},{"label":"Cota mínima absoluta de la malla","value":289.35,"unit":"m","source":"Malla de proyecto y origen altimétrico 285 m","status":"derivado"},{"label":"Cota máxima absoluta de la malla","value":290.95,"unit":"m","source":"Malla de proyecto y origen altimétrico 285 m","status":"derivado"},{"label":"Volumen geométrico bruto","value":0.672,"unit":"m³","source":"Malla cerrada del elemento","status":"derivado"}],"notes":["Las dimensiones documentadas proceden de anotaciones o cuadros; la caja y el volumen se calculan a partir de la malla.","El volumen es exclusivamente geométrico y bruto; no representa una medición neta de material ni una cantidad de compra."]} | {"documentId":"ARQ-OF-20260710","title":"Planos de arquitectura del edificio de oficinas","date":"2026-07-10","sheet":"Arquitectura A101 / p. 3, A103 / p. 5, A106 / p. 8; A301Cuadro de materiales "} | ["El plano general de 2026-07-31 mantiene el edificio de oficinas de 200 m², mientras documentación anterior indica su supresión. Se conserva lo dibujado, pendiente de confirmación de la propiedad y del equipo de diseño.","Envolvente exterior controlada por la planta de arquitectura; no se han modelado individualmente todas las capas de acabado.","Registro de líneas del PDF general, envolvente de 20 × 10 m; eje local 1 al norte y acceso del lado A al oeste. Estimación de trabajo de implantación de ±0,15 m, pendiente de CAD; no constituye una precisión topográfica garantizada."] | {"horizontalStatus":"derivado","verticalStatus":"derivado","baseElevationM":285.95,"note":"Registro de líneas del PDF general, envolvente de 20 × 10 m; eje local 1 al norte y acceso del lado A al oeste. Estimación de trabajo de implantación de ±0,15 m, pendiente de CAD; no constituye una precisión topográfica garantizada."} | {"Pset_WallCommon":{"IsExternal":{"value":true,"source":"ARQ-OF-20260710 · A101, A103 y alzados; elemento de la envolvente exterior identificada en planta","status":"known"}}} | {"boundingBoxM":{"min":[15.016693,72.790942,4.35],"max":[17.124363,73.275107,5.95]},"extentsM":[2.10767,0.484165,1.6],"meshSurfaceM2":8.200001,"meshVolumeM3":0.672001,"closedSolid":true,"basis":"Geometría triangulada releída del IFC; envolventes y magnitudes no contractuales."} | {"material":true,"document":true,"quantities":true,"containerGuid":"3ztlotcerHPueDgxP84R6z","containerName":"Planta baja"} | {"id":"architecture","name":"Arquitectura"} | {"profileId":"block_masonry","name":"Fábrica de bloques · acabado mineral claro","materialName":"Bloque hueco de hormigón de árido ligero","physicalMaterialStatus":"known","physicalMaterialSource":"ARQ-OF-20260710 · Arquitectura A101 / p. 3, A103 / p. 5, A106 / p. 8; A301Cuadro de materiales ","appearanceStatus":"criterio_visual","appearanceBasis":"Bloque hueco documentado. Apariencia mineral clara para distinguir el cerramiento; no confirma un revoco ni su espesor.","note":"La apariencia gráfica no modifica ni confirma la especificación física del material."} | {"elementId":"office_0196","ifcGuid":"0X12GQS_1VkftN96dbvhpe","ifcClass":"IfcWall","buildingId":"office","buildingName":"Edificio de oficinas","sourceDocumentId":"ARQ-OF-20260710","sourceRepresentationKind":"documentary_mesh"} | {"layerId":"architecture","layerName":"Arquitectura","role":"Muro","basis":"Clasificación por función del elemento; no modifica las especificaciones documentales."} | architecture | {"profileId":"block_masonry","name":"Fábrica de bloques · acabado mineral claro","status":"criterio_visual","basis":"Bloque hueco documentado. Apariencia mineral clara para distinguir el cerramiento; no confirma un revoco ni su espesor.","physicalMaterialUnchanged":true} | ARQ-OF-20260710 · Arquitectura A101 / p. 3, A103 / p. 5, A106 / p. 8; A301Cuadro de materiales | Dimensiones contrastadas con los planos; reconstrucción geométrica a partir de documentación de diseño. | 0.2 | Muros segmentados con huecos reales para puertas y ventanas. | Envolvente exterior controlada por la planta de arquitectura; no se han modelado individualmente todas las capas de acabado. | Registro de líneas del PDF general, envolvente de 20 × 10 m; eje local 1 al norte y acceso del lado A al oeste. Estimación de trabajo de implantación de ±0,15 m, pendiente de CAD; no constituye una precisión topográfica garantizada. | Arquitectura | ARQ-OF-20260710 · Arquitectura A101 / p. 3, A103 / p. 5, A106 / p. 8; A301Cuadro de materiales | 285.95 | Arquitectura | Fábrica de bloques · acabado mineral claro | block_masonry | [0.843137,0.823529,0.772549] | 0.96 | 0 | Bloque hueco documentado. Apariencia mineral clara para distinguir el cerramiento; no confirma un revoco ni su espesor. | Arquitectura; BIM · Arquitectura | El plano general de 2026-07-31 mantiene el edificio de oficinas de 200 m², mientras documentación anterior indica su supresión. Se conserva lo dibujado, pendiente de confirmación de la propiedad y del equipo de diseño.
Edificio de oficinas · Fábrica de bloques huecos de hormigón de 200 mm · eje 3 · tramo 04 | Planos de arquitectura del edificio de oficinas | Bloque hueco de hormigón de árido ligero | 0.2 × 0.9 × 1.1 | 285.95 | 287.05 | 0.198 | office_0197 | yes | 0.918853 | 0.32072 | 1.1 | 2.78 | 0.198 | office | Edificio de oficinas | {"name":"Bloque hueco de hormigón de árido ligero","source":"ARQ-OF-20260710 · Arquitectura A101 / p. 3, A103 / p. 5, A106 / p. 8; A301Cuadro de materiales ","status":"known"} | {"documented":[{"label":"Espesor del muro","value":0.2,"unit":"m","source":"ARQ-OF-20260710 · Arquitectura A101 / p. 3, A103 / p. 5, A106 / p. 8; A301Cuadro de materiales ","status":"documentado"}],"geometry":[{"label":"Dimensiones de la caja local del elemento (X, Y, Z)","value":"0.2 × 0.9 × 1.1","unit":"m","source":"Malla triangulada del elemento en ejes locales del edificio","status":"derivado"},{"label":"Cota mínima absoluta de la malla","value":285.95,"unit":"m","source":"Malla de proyecto y origen altimétrico 285 m","status":"derivado"},{"label":"Cota máxima absoluta de la malla","value":287.05,"unit":"m","source":"Malla de proyecto y origen altimétrico 285 m","status":"derivado"},{"label":"Volumen geométrico bruto","value":0.198,"unit":"m³","source":"Malla cerrada del elemento","status":"derivado"}],"notes":["Las dimensiones documentadas proceden de anotaciones o cuadros; la caja y el volumen se calculan a partir de la malla.","El volumen es exclusivamente geométrico y bruto; no representa una medición neta de material ni una cantidad de compra."]} | {"documentId":"ARQ-OF-20260710","title":"Planos de arquitectura del edificio de oficinas","date":"2026-07-10","sheet":"Arquitectura A101 / p. 3, A103 / p. 5, A106 / p. 8; A301Cuadro de materiales "} | ["El plano general de 2026-07-31 mantiene el edificio de oficinas de 200 m², mientras documentación anterior indica su supresión. Se conserva lo dibujado, pendiente de confirmación de la propiedad y del equipo de diseño.","Envolvente exterior controlada por la planta de arquitectura; no se han modelado individualmente todas las capas de acabado.","Registro de líneas del PDF general, envolvente de 20 × 10 m; eje local 1 al norte y acceso del lado A al oeste. Estimación de trabajo de implantación de ±0,15 m, pendiente de CAD; no constituye una precisión topográfica garantizada."] | {"horizontalStatus":"derivado","verticalStatus":"derivado","baseElevationM":285.95,"note":"Registro de líneas del PDF general, envolvente de 20 × 10 m; eje local 1 al norte y acceso del lado A al oeste. Estimación de trabajo de implantación de ±0,15 m, pendiente de CAD; no constituye una precisión topográfica garantizada."} | {"Pset_WallCommon":{"IsExternal":{"value":true,"source":"ARQ-OF-20260710 · A101, A103 y alzados; elemento de la envolvente exterior identificada en planta","status":"known"}}} | {"boundingBoxM":{"min":[17.097123,72.668359,0.95],"max":[18.015976,72.989079,2.05]},"extentsM":[0.918853,0.32072,1.1],"meshSurfaceM2":2.780001,"meshVolumeM3":0.198,"closedSolid":true,"basis":"Geometría triangulada releída del IFC; envolventes y magnitudes no contractuales."} | {"material":true,"document":true,"quantities":true,"containerGuid":"3ztlotcerHPueDgxP84R6z","containerName":"Planta baja"} | {"id":"architecture","name":"Arquitectura"} | {"profileId":"block_masonry","name":"Fábrica de bloques · acabado mineral claro","materialName":"Bloque hueco de hormigón de árido ligero","physicalMaterialStatus":"known","physicalMaterialSource":"ARQ-OF-20260710 · Arquitectura A101 / p. 3, A103 / p. 5, A106 / p. 8; A301Cuadro de materiales ","appearanceStatus":"criterio_visual","appearanceBasis":"Bloque hueco documentado. Apariencia mineral clara para distinguir el cerramiento; no confirma un revoco ni su espesor.","note":"La apariencia gráfica no modifica ni confirma la especificación física del material."} | {"elementId":"office_0197","ifcGuid":"2vwP1NiP5Kuw$PVozAUvHg","ifcClass":"IfcWall","buildingId":"office","buildingName":"Edificio de oficinas","sourceDocumentId":"ARQ-OF-20260710","sourceRepresentationKind":"documentary_mesh"} | {"layerId":"architecture","layerName":"Arquitectura","role":"Muro","basis":"Clasificación por función del elemento; no modifica las especificaciones documentales."} | architecture | {"profileId":"block_masonry","name":"Fábrica de bloques · acabado mineral claro","status":"criterio_visual","basis":"Bloque hueco documentado. Apariencia mineral clara para distinguir el cerramiento; no confirma un revoco ni su espesor.","physicalMaterialUnchanged":true} | ARQ-OF-20260710 · Arquitectura A101 / p. 3, A103 / p. 5, A106 / p. 8; A301Cuadro de materiales | Dimensiones contrastadas con los planos; reconstrucción geométrica a partir de documentación de diseño. | 0.2 | Muros segmentados con huecos reales para puertas y ventanas. | Envolvente exterior controlada por la planta de arquitectura; no se han modelado individualmente todas las capas de acabado. | Registro de líneas del PDF general, envolvente de 20 × 10 m; eje local 1 al norte y acceso del lado A al oeste. Estimación de trabajo de implantación de ±0,15 m, pendiente de CAD; no constituye una precisión topográfica garantizada. | Arquitectura | ARQ-OF-20260710 · Arquitectura A101 / p. 3, A103 / p. 5, A106 / p. 8; A301Cuadro de materiales | 285.95 | Arquitectura | Fábrica de bloques · acabado mineral claro | block_masonry | [0.843137,0.823529,0.772549] | 0.96 | 0 | Bloque hueco documentado. Apariencia mineral clara para distinguir el cerramiento; no confirma un revoco ni su espesor. | Arquitectura; BIM · Arquitectura | El plano general de 2026-07-31 mantiene el edificio de oficinas de 200 m², mientras documentación anterior indica su supresión. Se conserva lo dibujado, pendiente de confirmación de la propiedad y del equipo de diseño.
Edificio de oficinas · Fábrica de bloques huecos de hormigón de 200 mm · eje 3 · tramo 05 | Planos de arquitectura del edificio de oficinas | Bloque hueco de hormigón de árido ligero | 0.2 × 0.9 × 1.6 | 289.35 | 290.95 | 0.288 | office_0198 | yes | 0.918853 | 0.32072 | 1.6 | 3.88 | 0.288 | office | Edificio de oficinas | {"name":"Bloque hueco de hormigón de árido ligero","source":"ARQ-OF-20260710 · Arquitectura A101 / p. 3, A103 / p. 5, A106 / p. 8; A301Cuadro de materiales ","status":"known"} | {"documented":[{"label":"Espesor del muro","value":0.2,"unit":"m","source":"ARQ-OF-20260710 · Arquitectura A101 / p. 3, A103 / p. 5, A106 / p. 8; A301Cuadro de materiales ","status":"documentado"}],"geometry":[{"label":"Dimensiones de la caja local del elemento (X, Y, Z)","value":"0.2 × 0.9 × 1.6","unit":"m","source":"Malla triangulada del elemento en ejes locales del edificio","status":"derivado"},{"label":"Cota mínima absoluta de la malla","value":289.35,"unit":"m","source":"Malla de proyecto y origen altimétrico 285 m","status":"derivado"},{"label":"Cota máxima absoluta de la malla","value":290.95,"unit":"m","source":"Malla de proyecto y origen altimétrico 285 m","status":"derivado"},{"label":"Volumen geométrico bruto","value":0.288,"unit":"m³","source":"Malla cerrada del elemento","status":"derivado"}],"notes":["Las dimensiones documentadas proceden de anotaciones o cuadros; la caja y el volumen se calculan a partir de la malla.","El volumen es exclusivamente geométrico y bruto; no representa una medición neta de material ni una cantidad de compra."]} | {"documentId":"ARQ-OF-20260710","title":"Planos de arquitectura del edificio de oficinas","date":"2026-07-10","sheet":"Arquitectura A101 / p. 3, A103 / p. 5, A106 / p. 8; A301Cuadro de materiales "} | ["El plano general de 2026-07-31 mantiene el edificio de oficinas de 200 m², mientras documentación anterior indica su supresión. Se conserva lo dibujado, pendiente de confirmación de la propiedad y del equipo de diseño.","Envolvente exterior controlada por la planta de arquitectura; no se han modelado individualmente todas las capas de acabado.","Registro de líneas del PDF general, envolvente de 20 × 10 m; eje local 1 al norte y acceso del lado A al oeste. Estimación de trabajo de implantación de ±0,15 m, pendiente de CAD; no constituye una precisión topográfica garantizada."] | {"horizontalStatus":"derivado","verticalStatus":"derivado","baseElevationM":285.95,"note":"Registro de líneas del PDF general, envolvente de 20 × 10 m; eje local 1 al norte y acceso del lado A al oeste. Estimación de trabajo de implantación de ±0,15 m, pendiente de CAD; no constituye una precisión topográfica garantizada."} | {"Pset_WallCommon":{"IsExternal":{"value":true,"source":"ARQ-OF-20260710 · A101, A103 y alzados; elemento de la envolvente exterior identificada en planta","status":"known"}}} | {"boundingBoxM":{"min":[17.097123,72.668359,4.35],"max":[18.015976,72.989079,5.95]},"extentsM":[0.918853,0.32072,1.6],"meshSurfaceM2":3.880001,"meshVolumeM3":0.288,"closedSolid":true,"basis":"Geometría triangulada releída del IFC; envolventes y magnitudes no contractuales."} | {"material":true,"document":true,"quantities":true,"containerGuid":"3ztlotcerHPueDgxP84R6z","containerName":"Planta baja"} | {"id":"architecture","name":"Arquitectura"} | {"profileId":"block_masonry","name":"Fábrica de bloques · acabado mineral claro","materialName":"Bloque hueco de hormigón de árido ligero","physicalMaterialStatus":"known","physicalMaterialSource":"ARQ-OF-20260710 · Arquitectura A101 / p. 3, A103 / p. 5, A106 / p. 8; A301Cuadro de materiales ","appearanceStatus":"criterio_visual","appearanceBasis":"Bloque hueco documentado. Apariencia mineral clara para distinguir el cerramiento; no confirma un revoco ni su espesor.","note":"La apariencia gráfica no modifica ni confirma la especificación física del material."} | {"elementId":"office_0198","ifcGuid":"2hN4uNMn9LgvCBFr5hjSrh","ifcClass":"IfcWall","buildingId":"office","buildingName":"Edificio de oficinas","sourceDocumentId":"ARQ-OF-20260710","sourceRepresentationKind":"documentary_mesh"} | {"layerId":"architecture","layerName":"Arquitectura","role":"Muro","basis":"Clasificación por función del elemento; no modifica las especificaciones documentales."} | architecture | {"profileId":"block_masonry","name":"Fábrica de bloques · acabado mineral claro","status":"criterio_visual","basis":"Bloque hueco documentado. Apariencia mineral clara para distinguir el cerramiento; no confirma un revoco ni su espesor.","physicalMaterialUnchanged":true} | ARQ-OF-20260710 · Arquitectura A101 / p. 3, A103 / p. 5, A106 / p. 8; A301Cuadro de materiales | Dimensiones contrastadas con los planos; reconstrucción geométrica a partir de documentación de diseño. | 0.2 | Muros segmentados con huecos reales para puertas y ventanas. | Envolvente exterior controlada por la planta de arquitectura; no se han modelado individualmente todas las capas de acabado. | Registro de líneas del PDF general, envolvente de 20 × 10 m; eje local 1 al norte y acceso del lado A al oeste. Estimación de trabajo de implantación de ±0,15 m, pendiente de CAD; no constituye una precisión topográfica garantizada. | Arquitectura | ARQ-OF-20260710 · Arquitectura A101 / p. 3, A103 / p. 5, A106 / p. 8; A301Cuadro de materiales | 285.95 | Arquitectura | Fábrica de bloques · acabado mineral claro | block_masonry | [0.843137,0.823529,0.772549] | 0.96 | 0 | Bloque hueco documentado. Apariencia mineral clara para distinguir el cerramiento; no confirma un revoco ni su espesor. | Arquitectura; BIM · Arquitectura | El plano general de 2026-07-31 mantiene el edificio de oficinas de 200 m², mientras documentación anterior indica su supresión. Se conserva lo dibujado, pendiente de confirmación de la propiedad y del equipo de diseño.
Edificio de oficinas · Fábrica de bloques huecos de hormigón de 200 mm · eje 3 · tramo 06 | Planos de arquitectura del edificio de oficinas | Bloque hueco de hormigón de árido ligero | 0.2 × 0.9 × 1.1 | 285.95 | 287.05 | 0.198 | office_0199 | yes | 0.918854 | 0.32072 | 1.1 | 2.78 | 0.198 | office | Edificio de oficinas | {"name":"Bloque hueco de hormigón de árido ligero","source":"ARQ-OF-20260710 · Arquitectura A101 / p. 3, A103 / p. 5, A106 / p. 8; A301Cuadro de materiales ","status":"known"} | {"documented":[{"label":"Espesor del muro","value":0.2,"unit":"m","source":"ARQ-OF-20260710 · Arquitectura A101 / p. 3, A103 / p. 5, A106 / p. 8; A301Cuadro de materiales ","status":"documentado"}],"geometry":[{"label":"Dimensiones de la caja local del elemento (X, Y, Z)","value":"0.2 × 0.9 × 1.1","unit":"m","source":"Malla triangulada del elemento en ejes locales del edificio","status":"derivado"},{"label":"Cota mínima absoluta de la malla","value":285.95,"unit":"m","source":"Malla de proyecto y origen altimétrico 285 m","status":"derivado"},{"label":"Cota máxima absoluta de la malla","value":287.05,"unit":"m","source":"Malla de proyecto y origen altimétrico 285 m","status":"derivado"},{"label":"Volumen geométrico bruto","value":0.198,"unit":"m³","source":"Malla cerrada del elemento","status":"derivado"}],"notes":["Las dimensiones documentadas proceden de anotaciones o cuadros; la caja y el volumen se calculan a partir de la malla.","El volumen es exclusivamente geométrico y bruto; no representa una medición neta de material ni una cantidad de compra."]} | {"documentId":"ARQ-OF-20260710","title":"Planos de arquitectura del edificio de oficinas","date":"2026-07-10","sheet":"Arquitectura A101 / p. 3, A103 / p. 5, A106 / p. 8; A301Cuadro de materiales "} | ["El plano general de 2026-07-31 mantiene el edificio de oficinas de 200 m², mientras documentación anterior indica su supresión. Se conserva lo dibujado, pendiente de confirmación de la propiedad y del equipo de diseño.","Envolvente exterior controlada por la planta de arquitectura; no se han modelado individualmente todas las capas de acabado.","Registro de líneas del PDF general, envolvente de 20 × 10 m; eje local 1 al norte y acceso del lado A al oeste. Estimación de trabajo de implantación de ±0,15 m, pendiente de CAD; no constituye una precisión topográfica garantizada."] | {"horizontalStatus":"derivado","verticalStatus":"derivado","baseElevationM":285.95,"note":"Registro de líneas del PDF general, envolvente de 20 × 10 m; eje local 1 al norte y acceso del lado A al oeste. Estimación de trabajo de implantación de ±0,15 m, pendiente de CAD; no constituye una precisión topográfica garantizada."} | {"Pset_WallCommon":{"IsExternal":{"value":true,"source":"ARQ-OF-20260710 · A101, A103 y alzados; elemento de la envolvente exterior identificada en planta","status":"known"}}} | {"boundingBoxM":{"min":[17.988735,72.545775,0.95],"max":[18.907589,72.866495,2.05]},"extentsM":[0.918854,0.32072,1.1],"meshSurfaceM2":2.78,"meshVolumeM3":0.198,"closedSolid":true,"basis":"Geometría triangulada releída del IFC; envolventes y magnitudes no contractuales."} | {"material":true,"document":true,"quantities":true,"containerGuid":"3ztlotcerHPueDgxP84R6z","containerName":"Planta baja"} | {"id":"architecture","name":"Arquitectura"} | {"profileId":"block_masonry","name":"Fábrica de bloques · acabado mineral claro","materialName":"Bloque hueco de hormigón de árido ligero","physicalMaterialStatus":"known","physicalMaterialSource":"ARQ-OF-20260710 · Arquitectura A101 / p. 3, A103 / p. 5, A106 / p. 8; A301Cuadro de materiales ","appearanceStatus":"criterio_visual","appearanceBasis":"Bloque hueco documentado. Apariencia mineral clara para distinguir el cerramiento; no confirma un revoco ni su espesor.","note":"La apariencia gráfica no modifica ni confirma la especificación física del material."} | {"elementId":"office_0199","ifcGuid":"3IocYjIXnGSO8n3xw4efRm","ifcClass":"IfcWall","buildingId":"office","buildingName":"Edificio de oficinas","sourceDocumentId":"ARQ-OF-20260710","sourceRepresentationKind":"documentary_mesh"} | {"layerId":"architecture","layerName":"Arquitectura","role":"Muro","basis":"Clasificación por función del elemento; no modifica las especificaciones documentales."} | architecture | {"profileId":"block_masonry","name":"Fábrica de bloques · acabado mineral claro","status":"criterio_visual","basis":"Bloque hueco documentado. Apariencia mineral clara para distinguir el cerramiento; no confirma un revoco ni su espesor.","physicalMaterialUnchanged":true} | ARQ-OF-20260710 · Arquitectura A101 / p. 3, A103 / p. 5, A106 / p. 8; A301Cuadro de materiales | Dimensiones contrastadas con los planos; reconstrucción geométrica a partir de documentación de diseño. | 0.2 | Muros segmentados con huecos reales para puertas y ventanas. | Envolvente exterior controlada por la planta de arquitectura; no se han modelado individualmente todas las capas de acabado. | Registro de líneas del PDF general, envolvente de 20 × 10 m; eje local 1 al norte y acceso del lado A al oeste. Estimación de trabajo de implantación de ±0,15 m, pendiente de CAD; no constituye una precisión topográfica garantizada. | Arquitectura | ARQ-OF-20260710 · Arquitectura A101 / p. 3, A103 / p. 5, A106 / p. 8; A301Cuadro de materiales | 285.95 | Arquitectura | Fábrica de bloques · acabado mineral claro | block_masonry | [0.843137,0.823529,0.772549] | 0.96 | 0 | Bloque hueco documentado. Apariencia mineral clara para distinguir el cerramiento; no confirma un revoco ni su espesor. | Arquitectura; BIM · Arquitectura | El plano general de 2026-07-31 mantiene el edificio de oficinas de 200 m², mientras documentación anterior indica su supresión. Se conserva lo dibujado, pendiente de confirmación de la propiedad y del equipo de diseño.
Edificio de oficinas · Fábrica de bloques huecos de hormigón de 200 mm · eje 3 · tramo 07 | Planos de arquitectura del edificio de oficinas | Bloque hueco de hormigón de árido ligero | 0.2 × 0.9 × 2.3 | 287.05 | 289.35 | 0.414 | office_0200 | yes | 0.918854 | 0.32072 | 2.3 | 5.42 | 0.414 | office | Edificio de oficinas | {"name":"Bloque hueco de hormigón de árido ligero","source":"ARQ-OF-20260710 · Arquitectura A101 / p. 3, A103 / p. 5, A106 / p. 8; A301Cuadro de materiales ","status":"known"} | {"documented":[{"label":"Espesor del muro","value":0.2,"unit":"m","source":"ARQ-OF-20260710 · Arquitectura A101 / p. 3, A103 / p. 5, A106 / p. 8; A301Cuadro de materiales ","status":"documentado"}],"geometry":[{"label":"Dimensiones de la caja local del elemento (X, Y, Z)","value":"0.2 × 0.9 × 2.3","unit":"m","source":"Malla triangulada del elemento en ejes locales del edificio","status":"derivado"},{"label":"Cota mínima absoluta de la malla","value":287.05,"unit":"m","source":"Malla de proyecto y origen altimétrico 285 m","status":"derivado"},{"label":"Cota máxima absoluta de la malla","value":289.35,"unit":"m","source":"Malla de proyecto y origen altimétrico 285 m","status":"derivado"},{"label":"Volumen geométrico bruto","value":0.414,"unit":"m³","source":"Malla cerrada del elemento","status":"derivado"}],"notes":["Las dimensiones documentadas proceden de anotaciones o cuadros; la caja y el volumen se calculan a partir de la malla.","El volumen es exclusivamente geométrico y bruto; no representa una medición neta de material ni una cantidad de compra."]} | {"documentId":"ARQ-OF-20260710","title":"Planos de arquitectura del edificio de oficinas","date":"2026-07-10","sheet":"Arquitectura A101 / p. 3, A103 / p. 5, A106 / p. 8; A301Cuadro de materiales "} | ["El plano general de 2026-07-31 mantiene el edificio de oficinas de 200 m², mientras documentación anterior indica su supresión. Se conserva lo dibujado, pendiente de confirmación de la propiedad y del equipo de diseño.","Envolvente exterior controlada por la planta de arquitectura; no se han modelado individualmente todas las capas de acabado.","Registro de líneas del PDF general, envolvente de 20 × 10 m; eje local 1 al norte y acceso del lado A al oeste. Estimación de trabajo de implantación de ±0,15 m, pendiente de CAD; no constituye una precisión topográfica garantizada."] | {"horizontalStatus":"derivado","verticalStatus":"derivado","baseElevationM":285.95,"note":"Registro de líneas del PDF general, envolvente de 20 × 10 m; eje local 1 al norte y acceso del lado A al oeste. Estimación de trabajo de implantación de ±0,15 m, pendiente de CAD; no constituye una precisión topográfica garantizada."} | {"Pset_WallCommon":{"IsExternal":{"value":true,"source":"ARQ-OF-20260710 · A101, A103 y alzados; elemento de la envolvente exterior identificada en planta","status":"known"}}} | {"boundingBoxM":{"min":[17.988735,72.545775,2.05],"max":[18.907589,72.866495,4.35]},"extentsM":[0.918854,0.32072,2.3],"meshSurfaceM2":5.420001,"meshVolumeM3":0.414,"closedSolid":true,"basis":"Geometría triangulada releída del IFC; envolventes y magnitudes no contractuales."} | {"material":true,"document":true,"quantities":true,"containerGuid":"3ztlotcerHPueDgxP84R6z","containerName":"Planta baja"} | {"id":"architecture","name":"Arquitectura"} | {"profileId":"block_masonry","name":"Fábrica de bloques · acabado mineral claro","materialName":"Bloque hueco de hormigón de árido ligero","physicalMaterialStatus":"known","physicalMaterialSource":"ARQ-OF-20260710 · Arquitectura A101 / p. 3, A103 / p. 5, A106 / p. 8; A301Cuadro de materiales ","appearanceStatus":"criterio_visual","appearanceBasis":"Bloque hueco documentado. Apariencia mineral clara para distinguir el cerramiento; no confirma un revoco ni su espesor.","note":"La apariencia gráfica no modifica ni confirma la especificación física del material."} | {"elementId":"office_0200","ifcGuid":"1I5e7gaNbVhenWfyljGKIL","ifcClass":"IfcWall","buildingId":"office","buildingName":"Edificio de oficinas","sourceDocumentId":"ARQ-OF-20260710","sourceRepresentationKind":"documentary_mesh"} | {"layerId":"architecture","layerName":"Arquitectura","role":"Muro","basis":"Clasificación por función del elemento; no modifica las especificaciones documentales."} | architecture | {"profileId":"block_masonry","name":"Fábrica de bloques · acabado mineral claro","status":"criterio_visual","basis":"Bloque hueco documentado. Apariencia mineral clara para distinguir el cerramiento; no confirma un revoco ni su espesor.","physicalMaterialUnchanged":true} | ARQ-OF-20260710 · Arquitectura A101 / p. 3, A103 / p. 5, A106 / p. 8; A301Cuadro de materiales | Dimensiones contrastadas con los planos; reconstrucción geométrica a partir de documentación de diseño. | 0.2 | Muros segmentados con huecos reales para puertas y ventanas. | Envolvente exterior controlada por la planta de arquitectura; no se han modelado individualmente todas las capas de acabado. | Registro de líneas del PDF general, envolvente de 20 × 10 m; eje local 1 al norte y acceso del lado A al oeste. Estimación de trabajo de implantación de ±0,15 m, pendiente de CAD; no constituye una precisión topográfica garantizada. | Arquitectura | ARQ-OF-20260710 · Arquitectura A101 / p. 3, A103 / p. 5, A106 / p. 8; A301Cuadro de materiales | 285.95 | Arquitectura | Fábrica de bloques · acabado mineral claro | block_masonry | [0.843137,0.823529,0.772549] | 0.96 | 0 | Bloque hueco documentado. Apariencia mineral clara para distinguir el cerramiento; no confirma un revoco ni su espesor. | Arquitectura; BIM · Arquitectura | El plano general de 2026-07-31 mantiene el edificio de oficinas de 200 m², mientras documentación anterior indica su supresión. Se conserva lo dibujado, pendiente de confirmación de la propiedad y del equipo de diseño.
Edificio de oficinas · Fábrica de bloques huecos de hormigón de 200 mm · eje 3 · tramo 08 | Planos de arquitectura del edificio de oficinas | Bloque hueco de hormigón de árido ligero | 0.2 × 0.9 × 1.6 | 289.35 | 290.95 | 0.288 | office_0201 | yes | 0.918854 | 0.32072 | 1.6 | 3.88 | 0.288 | office | Edificio de oficinas | {"name":"Bloque hueco de hormigón de árido ligero","source":"ARQ-OF-20260710 · Arquitectura A101 / p. 3, A103 / p. 5, A106 / p. 8; A301Cuadro de materiales ","status":"known"} | {"documented":[{"label":"Espesor del muro","value":0.2,"unit":"m","source":"ARQ-OF-20260710 · Arquitectura A101 / p. 3, A103 / p. 5, A106 / p. 8; A301Cuadro de materiales ","status":"documentado"}],"geometry":[{"label":"Dimensiones de la caja local del elemento (X, Y, Z)","value":"0.2 × 0.9 × 1.6","unit":"m","source":"Malla triangulada del elemento en ejes locales del edificio","status":"derivado"},{"label":"Cota mínima absoluta de la malla","value":289.35,"unit":"m","source":"Malla de proyecto y origen altimétrico 285 m","status":"derivado"},{"label":"Cota máxima absoluta de la malla","value":290.95,"unit":"m","source":"Malla de proyecto y origen altimétrico 285 m","status":"derivado"},{"label":"Volumen geométrico bruto","value":0.288,"unit":"m³","source":"Malla cerrada del elemento","status":"derivado"}],"notes":["Las dimensiones documentadas proceden de anotaciones o cuadros; la caja y el volumen se calculan a partir de la malla.","El volumen es exclusivamente geométrico y bruto; no representa una medición neta de material ni una cantidad de compra."]} | {"documentId":"ARQ-OF-20260710","title":"Planos de arquitectura del edificio de oficinas","date":"2026-07-10","sheet":"Arquitectura A101 / p. 3, A103 / p. 5, A106 / p. 8; A301Cuadro de materiales "} | ["El plano general de 2026-07-31 mantiene el edificio de oficinas de 200 m², mientras documentación anterior indica su supresión. Se conserva lo dibujado, pendiente de confirmación de la propiedad y del equipo de diseño.","Envolvente exterior controlada por la planta de arquitectura; no se han modelado individualmente todas las capas de acabado.","Registro de líneas del PDF general, envolvente de 20 × 10 m; eje local 1 al norte y acceso del lado A al oeste. Estimación de trabajo de implantación de ±0,15 m, pendiente de CAD; no constituye una precisión topográfica garantizada."] | {"horizontalStatus":"derivado","verticalStatus":"derivado","baseElevationM":285.95,"note":"Registro de líneas del PDF general, envolvente de 20 × 10 m; eje local 1 al norte y acceso del lado A al oeste. Estimación de trabajo de implantación de ±0,15 m, pendiente de CAD; no constituye una precisión topográfica garantizada."} | {"Pset_WallCommon":{"IsExternal":{"value":true,"source":"ARQ-OF-20260710 · A101, A103 y alzados; elemento de la envolvente exterior identificada en planta","status":"known"}}} | {"boundingBoxM":{"min":[17.988735,72.545775,4.35],"max":[18.907589,72.866495,5.95]},"extentsM":[0.918854,0.32072,1.6],"meshSurfaceM2":3.88,"meshVolumeM3":0.288,"closedSolid":true,"basis":"Geometría triangulada releída del IFC; envolventes y magnitudes no contractuales."} | {"material":true,"document":true,"quantities":true,"containerGuid":"3ztlotcerHPueDgxP84R6z","containerName":"Planta baja"} | {"id":"architecture","name":"Arquitectura"} | {"profileId":"block_masonry","name":"Fábrica de bloques · acabado mineral claro","materialName":"Bloque hueco de hormigón de árido ligero","physicalMaterialStatus":"known","physicalMaterialSource":"ARQ-OF-20260710 · Arquitectura A101 / p. 3, A103 / p. 5, A106 / p. 8; A301Cuadro de materiales ","appearanceStatus":"criterio_visual","appearanceBasis":"Bloque hueco documentado. Apariencia mineral clara para distinguir el cerramiento; no confirma un revoco ni su espesor.","note":"La apariencia gráfica no modifica ni confirma la especificación física del material."} | {"elementId":"office_0201","ifcGuid":"1A9ESG0WDUDelEn$du7UyA","ifcClass":"IfcWall","buildingId":"office","buildingName":"Edificio de oficinas","sourceDocumentId":"ARQ-OF-20260710","sourceRepresentationKind":"documentary_mesh"} | {"layerId":"architecture","layerName":"Arquitectura","role":"Muro","basis":"Clasificación por función del elemento; no modifica las especificaciones documentales."} | architecture | {"profileId":"block_masonry","name":"Fábrica de bloques · acabado mineral claro","status":"criterio_visual","basis":"Bloque hueco documentado. Apariencia mineral clara para distinguir el cerramiento; no confirma un revoco ni su espesor.","physicalMaterialUnchanged":true} | ARQ-OF-20260710 · Arquitectura A101 / p. 3, A103 / p. 5, A106 / p. 8; A301Cuadro de materiales | Dimensiones contrastadas con los planos; reconstrucción geométrica a partir de documentación de diseño. | 0.2 | Muros segmentados con huecos reales para puertas y ventanas. | Envolvente exterior controlada por la planta de arquitectura; no se han modelado individualmente todas las capas de acabado. | Registro de líneas del PDF general, envolvente de 20 × 10 m; eje local 1 al norte y acceso del lado A al oeste. Estimación de trabajo de implantación de ±0,15 m, pendiente de CAD; no constituye una precisión topográfica garantizada. | Arquitectura | ARQ-OF-20260710 · Arquitectura A101 / p. 3, A103 / p. 5, A106 / p. 8; A301Cuadro de materiales | 285.95 | Arquitectura | Fábrica de bloques · acabado mineral claro | block_masonry | [0.843137,0.823529,0.772549] | 0.96 | 0 | Bloque hueco documentado. Apariencia mineral clara para distinguir el cerramiento; no confirma un revoco ni su espesor. | Arquitectura; BIM · Arquitectura | El plano general de 2026-07-31 mantiene el edificio de oficinas de 200 m², mientras documentación anterior indica su supresión. Se conserva lo dibujado, pendiente de confirmación de la propiedad y del equipo de diseño.
Edificio de oficinas · Fábrica de bloques huecos de hormigón de 200 mm · eje 3 · tramo 09 | Planos de arquitectura del edificio de oficinas | Bloque hueco de hormigón de árido ligero | 0.2 × 0.9 × 1.1 | 285.95 | 287.05 | 0.198 | office_0202 | yes | 0.918854 | 0.320719 | 1.1 | 2.78 | 0.198 | office | Edificio de oficinas | {"name":"Bloque hueco de hormigón de árido ligero","source":"ARQ-OF-20260710 · Arquitectura A101 / p. 3, A103 / p. 5, A106 / p. 8; A301Cuadro de materiales ","status":"known"} | {"documented":[{"label":"Espesor del muro","value":0.2,"unit":"m","source":"ARQ-OF-20260710 · Arquitectura A101 / p. 3, A103 / p. 5, A106 / p. 8; A301Cuadro de materiales ","status":"documentado"}],"geometry":[{"label":"Dimensiones de la caja local del elemento (X, Y, Z)","value":"0.2 × 0.9 × 1.1","unit":"m","source":"Malla triangulada del elemento en ejes locales del edificio","status":"derivado"},{"label":"Cota mínima absoluta de la malla","value":285.95,"unit":"m","source":"Malla de proyecto y origen altimétrico 285 m","status":"derivado"},{"label":"Cota máxima absoluta de la malla","value":287.05,"unit":"m","source":"Malla de proyecto y origen altimétrico 285 m","status":"derivado"},{"label":"Volumen geométrico bruto","value":0.198,"unit":"m³","source":"Malla cerrada del elemento","status":"derivado"}],"notes":["Las dimensiones documentadas proceden de anotaciones o cuadros; la caja y el volumen se calculan a partir de la malla.","El volumen es exclusivamente geométrico y bruto; no representa una medición neta de material ni una cantidad de compra."]} | {"documentId":"ARQ-OF-20260710","title":"Planos de arquitectura del edificio de oficinas","date":"2026-07-10","sheet":"Arquitectura A101 / p. 3, A103 / p. 5, A106 / p. 8; A301Cuadro de materiales "} | ["El plano general de 2026-07-31 mantiene el edificio de oficinas de 200 m², mientras documentación anterior indica su supresión. Se conserva lo dibujado, pendiente de confirmación de la propiedad y del equipo de diseño.","Envolvente exterior controlada por la planta de arquitectura; no se han modelado individualmente todas las capas de acabado.","Registro de líneas del PDF general, envolvente de 20 × 10 m; eje local 1 al norte y acceso del lado A al oeste. Estimación de trabajo de implantación de ±0,15 m, pendiente de CAD; no constituye una precisión topográfica garantizada."] | {"horizontalStatus":"derivado","verticalStatus":"derivado","baseElevationM":285.95,"note":"Registro de líneas del PDF general, envolvente de 20 × 10 m; eje local 1 al norte y acceso del lado A al oeste. Estimación de trabajo de implantación de ±0,15 m, pendiente de CAD; no constituye una precisión topográfica garantizada."} | {"Pset_WallCommon":{"IsExternal":{"value":true,"source":"ARQ-OF-20260710 · A101, A103 y alzados; elemento de la envolvente exterior identificada en planta","status":"known"}}} | {"boundingBoxM":{"min":[18.880348,72.423192,0.95],"max":[19.799202,72.743911,2.05]},"extentsM":[0.918854,0.320719,1.1],"meshSurfaceM2":2.78,"meshVolumeM3":0.198,"closedSolid":true,"basis":"Geometría triangulada releída del IFC; envolventes y magnitudes no contractuales."} | {"material":true,"document":true,"quantities":true,"containerGuid":"3ztlotcerHPueDgxP84R6z","containerName":"Planta baja"} | {"id":"architecture","name":"Arquitectura"} | {"profileId":"block_masonry","name":"Fábrica de bloques · acabado mineral claro","materialName":"Bloque hueco de hormigón de árido ligero","physicalMaterialStatus":"known","physicalMaterialSource":"ARQ-OF-20260710 · Arquitectura A101 / p. 3, A103 / p. 5, A106 / p. 8; A301Cuadro de materiales ","appearanceStatus":"criterio_visual","appearanceBasis":"Bloque hueco documentado. Apariencia mineral clara para distinguir el cerramiento; no confirma un revoco ni su espesor.","note":"La apariencia gráfica no modifica ni confirma la especificación física del material."} | {"elementId":"office_0202","ifcGuid":"1caOmNGX1UnRZCBBLeO2ZY","ifcClass":"IfcWall","buildingId":"office","buildingName":"Edificio de oficinas","sourceDocumentId":"ARQ-OF-20260710","sourceRepresentationKind":"documentary_mesh"} | {"layerId":"architecture","layerName":"Arquitectura","role":"Muro","basis":"Clasificación por función del elemento; no modifica las especificaciones documentales."} | architecture | {"profileId":"block_masonry","name":"Fábrica de bloques · acabado mineral claro","status":"criterio_visual","basis":"Bloque hueco documentado. Apariencia mineral clara para distinguir el cerramiento; no confirma un revoco ni su espesor.","physicalMaterialUnchanged":true} | ARQ-OF-20260710 · Arquitectura A101 / p. 3, A103 / p. 5, A106 / p. 8; A301Cuadro de materiales | Dimensiones contrastadas con los planos; reconstrucción geométrica a partir de documentación de diseño. | 0.2 | Muros segmentados con huecos reales para puertas y ventanas. | Envolvente exterior controlada por la planta de arquitectura; no se han modelado individualmente todas las capas de acabado. | Registro de líneas del PDF general, envolvente de 20 × 10 m; eje local 1 al norte y acceso del lado A al oeste. Estimación de trabajo de implantación de ±0,15 m, pendiente de CAD; no constituye una precisión topográfica garantizada. | Arquitectura | ARQ-OF-20260710 · Arquitectura A101 / p. 3, A103 / p. 5, A106 / p. 8; A301Cuadro de materiales | 285.95 | Arquitectura | Fábrica de bloques · acabado mineral claro | block_masonry | [0.843137,0.823529,0.772549] | 0.96 | 0 | Bloque hueco documentado. Apariencia mineral clara para distinguir el cerramiento; no confirma un revoco ni su espesor. | Arquitectura; BIM · Arquitectura | El plano general de 2026-07-31 mantiene el edificio de oficinas de 200 m², mientras documentación anterior indica su supresión. Se conserva lo dibujado, pendiente de confirmación de la propiedad y del equipo de diseño.
Edificio de oficinas · Fábrica de bloques huecos de hormigón de 200 mm · eje 3 · tramo 10 | Planos de arquitectura del edificio de oficinas | Bloque hueco de hormigón de árido ligero | 0.2 × 0.9 × 1.6 | 289.35 | 290.95 | 0.288 | office_0203 | yes | 0.918854 | 0.320719 | 1.6 | 3.88 | 0.288 | office | Edificio de oficinas | {"name":"Bloque hueco de hormigón de árido ligero","source":"ARQ-OF-20260710 · Arquitectura A101 / p. 3, A103 / p. 5, A106 / p. 8; A301Cuadro de materiales ","status":"known"} | {"documented":[{"label":"Espesor del muro","value":0.2,"unit":"m","source":"ARQ-OF-20260710 · Arquitectura A101 / p. 3, A103 / p. 5, A106 / p. 8; A301Cuadro de materiales ","status":"documentado"}],"geometry":[{"label":"Dimensiones de la caja local del elemento (X, Y, Z)","value":"0.2 × 0.9 × 1.6","unit":"m","source":"Malla triangulada del elemento en ejes locales del edificio","status":"derivado"},{"label":"Cota mínima absoluta de la malla","value":289.35,"unit":"m","source":"Malla de proyecto y origen altimétrico 285 m","status":"derivado"},{"label":"Cota máxima absoluta de la malla","value":290.95,"unit":"m","source":"Malla de proyecto y origen altimétrico 285 m","status":"derivado"},{"label":"Volumen geométrico bruto","value":0.288,"unit":"m³","source":"Malla cerrada del elemento","status":"derivado"}],"notes":["Las dimensiones documentadas proceden de anotaciones o cuadros; la caja y el volumen se calculan a partir de la malla.","El volumen es exclusivamente geométrico y bruto; no representa una medición neta de material ni una cantidad de compra."]} | {"documentId":"ARQ-OF-20260710","title":"Planos de arquitectura del edificio de oficinas","date":"2026-07-10","sheet":"Arquitectura A101 / p. 3, A103 / p. 5, A106 / p. 8; A301Cuadro de materiales "} | ["El plano general de 2026-07-31 mantiene el edificio de oficinas de 200 m², mientras documentación anterior indica su supresión. Se conserva lo dibujado, pendiente de confirmación de la propiedad y del equipo de diseño.","Envolvente exterior controlada por la planta de arquitectura; no se han modelado individualmente todas las capas de acabado.","Registro de líneas del PDF general, envolvente de 20 × 10 m; eje local 1 al norte y acceso del lado A al oeste. Estimación de trabajo de implantación de ±0,15 m, pendiente de CAD; no constituye una precisión topográfica garantizada."] | {"horizontalStatus":"derivado","verticalStatus":"derivado","baseElevationM":285.95,"note":"Registro de líneas del PDF general, envolvente de 20 × 10 m; eje local 1 al norte y acceso del lado A al oeste. Estimación de trabajo de implantación de ±0,15 m, pendiente de CAD; no constituye una precisión topográfica garantizada."} | {"Pset_WallCommon":{"IsExternal":{"value":true,"source":"ARQ-OF-20260710 · A101, A103 y alzados; elemento de la envolvente exterior identificada en planta","status":"known"}}} | {"boundingBoxM":{"min":[18.880348,72.423192,4.35],"max":[19.799202,72.743911,5.95]},"extentsM":[0.918854,0.320719,1.6],"meshSurfaceM2":3.88,"meshVolumeM3":0.288,"closedSolid":true,"basis":"Geometría triangulada releída del IFC; envolventes y magnitudes no contractuales."} | {"material":true,"document":true,"quantities":true,"containerGuid":"3ztlotcerHPueDgxP84R6z","containerName":"Planta baja"} | {"id":"architecture","name":"Arquitectura"} | {"profileId":"block_masonry","name":"Fábrica de bloques · acabado mineral claro","materialName":"Bloque hueco de hormigón de árido ligero","physicalMaterialStatus":"known","physicalMaterialSource":"ARQ-OF-20260710 · Arquitectura A101 / p. 3, A103 / p. 5, A106 / p. 8; A301Cuadro de materiales ","appearanceStatus":"criterio_visual","appearanceBasis":"Bloque hueco documentado. Apariencia mineral clara para distinguir el cerramiento; no confirma un revoco ni su espesor.","note":"La apariencia gráfica no modifica ni confirma la especificación física del material."} | {"elementId":"office_0203","ifcGuid":"1fUkDb4_1G9OMV_Lx3ot4N","ifcClass":"IfcWall","buildingId":"office","buildingName":"Edificio de oficinas","sourceDocumentId":"ARQ-OF-20260710","sourceRepresentationKind":"documentary_mesh"} | {"layerId":"architecture","layerName":"Arquitectura","role":"Muro","basis":"Clasificación por función del elemento; no modifica las especificaciones documentales."} | architecture | {"profileId":"block_masonry","name":"Fábrica de bloques · acabado mineral claro","status":"criterio_visual","basis":"Bloque hueco documentado. Apariencia mineral clara para distinguir el cerramiento; no confirma un revoco ni su espesor.","physicalMaterialUnchanged":true} | ARQ-OF-20260710 · Arquitectura A101 / p. 3, A103 / p. 5, A106 / p. 8; A301Cuadro de materiales | Dimensiones contrastadas con los planos; reconstrucción geométrica a partir de documentación de diseño. | 0.2 | Muros segmentados con huecos reales para puertas y ventanas. | Envolvente exterior controlada por la planta de arquitectura; no se han modelado individualmente todas las capas de acabado. | Registro de líneas del PDF general, envolvente de 20 × 10 m; eje local 1 al norte y acceso del lado A al oeste. Estimación de trabajo de implantación de ±0,15 m, pendiente de CAD; no constituye una precisión topográfica garantizada. | Arquitectura | ARQ-OF-20260710 · Arquitectura A101 / p. 3, A103 / p. 5, A106 / p. 8; A301Cuadro de materiales | 285.95 | Arquitectura | Fábrica de bloques · acabado mineral claro | block_masonry | [0.843137,0.823529,0.772549] | 0.96 | 0 | Bloque hueco documentado. Apariencia mineral clara para distinguir el cerramiento; no confirma un revoco ni su espesor. | Arquitectura; BIM · Arquitectura | El plano general de 2026-07-31 mantiene el edificio de oficinas de 200 m², mientras documentación anterior indica su supresión. Se conserva lo dibujado, pendiente de confirmación de la propiedad y del equipo de diseño.
Edificio de oficinas · Fábrica de bloques huecos de hormigón de 200 mm · eje 3 · tramo 11 | Planos de arquitectura del edificio de oficinas | Bloque hueco de hormigón de árido ligero | 0.2 × 4.8 × 1.1 | 285.95 | 287.05 | 1.056 | office_0204 | yes | 4.78251 | 0.851915 | 1.1 | 12.92 | 1.056 | office | Edificio de oficinas | {"name":"Bloque hueco de hormigón de árido ligero","source":"ARQ-OF-20260710 · Arquitectura A101 / p. 3, A103 / p. 5, A106 / p. 8; A301Cuadro de materiales ","status":"known"} | {"documented":[{"label":"Espesor del muro","value":0.2,"unit":"m","source":"ARQ-OF-20260710 · Arquitectura A101 / p. 3, A103 / p. 5, A106 / p. 8; A301Cuadro de materiales ","status":"documentado"}],"geometry":[{"label":"Dimensiones de la caja local del elemento (X, Y, Z)","value":"0.2 × 4.8 × 1.1","unit":"m","source":"Malla triangulada del elemento en ejes locales del edificio","status":"derivado"},{"label":"Cota mínima absoluta de la malla","value":285.95,"unit":"m","source":"Malla de proyecto y origen altimétrico 285 m","status":"derivado"},{"label":"Cota máxima absoluta de la malla","value":287.05,"unit":"m","source":"Malla de proyecto y origen altimétrico 285 m","status":"derivado"},{"label":"Volumen geométrico bruto","value":1.056,"unit":"m³","source":"Malla cerrada del elemento","status":"derivado"}],"notes":["Las dimensiones documentadas proceden de anotaciones o cuadros; la caja y el volumen se calculan a partir de la malla.","El volumen es exclusivamente geométrico y bruto; no representa una medición neta de material ni una cantidad de compra."]} | {"documentId":"ARQ-OF-20260710","title":"Planos de arquitectura del edificio de oficinas","date":"2026-07-10","sheet":"Arquitectura A101 / p. 3, A103 / p. 5, A106 / p. 8; A301Cuadro de materiales "} | ["El plano general de 2026-07-31 mantiene el edificio de oficinas de 200 m², mientras documentación anterior indica su supresión. Se conserva lo dibujado, pendiente de confirmación de la propiedad y del equipo de diseño.","Envolvente exterior controlada por la planta de arquitectura; no se han modelado individualmente todas las capas de acabado.","Registro de líneas del PDF general, envolvente de 20 × 10 m; eje local 1 al norte y acceso del lado A al oeste. Estimación de trabajo de implantación de ±0,15 m, pendiente de CAD; no constituye una precisión topográfica garantizada."] | {"horizontalStatus":"derivado","verticalStatus":"derivado","baseElevationM":285.95,"note":"Registro de líneas del PDF general, envolvente de 20 × 10 m; eje local 1 al norte y acceso del lado A al oeste. Estimación de trabajo de implantación de ±0,15 m, pendiente de CAD; no constituye una precisión topográfica garantizada."} | {"Pset_WallCommon":{"IsExternal":{"value":true,"source":"ARQ-OF-20260710 · A101, A103 y alzados; elemento de la envolvente exterior identificada en planta","status":"known"}}} | {"boundingBoxM":{"min":[19.771961,71.769413,0.95],"max":[24.554469,72.621328,2.05]},"extentsM":[4.782508,0.851915,1.1],"meshSurfaceM2":12.919997,"meshVolumeM3":1.055999,"closedSolid":true,"basis":"Geometría triangulada releída del IFC; envolventes y magnitudes no contractuales."} | {"material":true,"document":true,"quantities":true,"containerGuid":"3ztlotcerHPueDgxP84R6z","containerName":"Planta baja"} | {"id":"architecture","name":"Arquitectura"} | {"profileId":"block_masonry","name":"Fábrica de bloques · acabado mineral claro","materialName":"Bloque hueco de hormigón de árido ligero","physicalMaterialStatus":"known","physicalMaterialSource":"ARQ-OF-20260710 · Arquitectura A101 / p. 3, A103 / p. 5, A106 / p. 8; A301Cuadro de materiales ","appearanceStatus":"criterio_visual","appearanceBasis":"Bloque hueco documentado. Apariencia mineral clara para distinguir el cerramiento; no confirma un revoco ni su espesor.","note":"La apariencia gráfica no modifica ni confirma la especificación física del material."} | {"elementId":"office_0204","ifcGuid":"32PTBJEvzQGgWL2ypGUAuQ","ifcClass":"IfcWall","buildingId":"office","buildingName":"Edificio de oficinas","sourceDocumentId":"ARQ-OF-20260710","sourceRepresentationKind":"documentary_mesh"} | {"layerId":"architecture","layerName":"Arquitectura","role":"Muro","basis":"Clasificación por función del elemento; no modifica las especificaciones documentales."} | architecture | {"profileId":"block_masonry","name":"Fábrica de bloques · acabado mineral claro","status":"criterio_visual","basis":"Bloque hueco documentado. Apariencia mineral clara para distinguir el cerramiento; no confirma un revoco ni su espesor.","physicalMaterialUnchanged":true} | ARQ-OF-20260710 · Arquitectura A101 / p. 3, A103 / p. 5, A106 / p. 8; A301Cuadro de materiales | Dimensiones contrastadas con los planos; reconstrucción geométrica a partir de documentación de diseño. | 0.2 | Muros segmentados con huecos reales para puertas y ventanas. | Envolvente exterior controlada por la planta de arquitectura; no se han modelado individualmente todas las capas de acabado. | Registro de líneas del PDF general, envolvente de 20 × 10 m; eje local 1 al norte y acceso del lado A al oeste. Estimación de trabajo de implantación de ±0,15 m, pendiente de CAD; no constituye una precisión topográfica garantizada. | Arquitectura | ARQ-OF-20260710 · Arquitectura A101 / p. 3, A103 / p. 5, A106 / p. 8; A301Cuadro de materiales | 285.95 | Arquitectura | Fábrica de bloques · acabado mineral claro | block_masonry | [0.843137,0.823529,0.772549] | 0.96 | 0 | Bloque hueco documentado. Apariencia mineral clara para distinguir el cerramiento; no confirma un revoco ni su espesor. | Arquitectura; BIM · Arquitectura | El plano general de 2026-07-31 mantiene el edificio de oficinas de 200 m², mientras documentación anterior indica su supresión. Se conserva lo dibujado, pendiente de confirmación de la propiedad y del equipo de diseño.
Edificio de oficinas · Fábrica de bloques huecos de hormigón de 200 mm · eje 3 · tramo 12 | Planos de arquitectura del edificio de oficinas | Bloque hueco de hormigón de árido ligero | 0.2 × 4.8 × 2.3 | 287.05 | 289.35 | 2.208 | office_0205 | yes | 4.78251 | 0.851915 | 2.3 | 24.92 | 2.208 | office | Edificio de oficinas | {"name":"Bloque hueco de hormigón de árido ligero","source":"ARQ-OF-20260710 · Arquitectura A101 / p. 3, A103 / p. 5, A106 / p. 8; A301Cuadro de materiales ","status":"known"} | {"documented":[{"label":"Espesor del muro","value":0.2,"unit":"m","source":"ARQ-OF-20260710 · Arquitectura A101 / p. 3, A103 / p. 5, A106 / p. 8; A301Cuadro de materiales ","status":"documentado"}],"geometry":[{"label":"Dimensiones de la caja local del elemento (X, Y, Z)","value":"0.2 × 4.8 × 2.3","unit":"m","source":"Malla triangulada del elemento en ejes locales del edificio","status":"derivado"},{"label":"Cota mínima absoluta de la malla","value":287.05,"unit":"m","source":"Malla de proyecto y origen altimétrico 285 m","status":"derivado"},{"label":"Cota máxima absoluta de la malla","value":289.35,"unit":"m","source":"Malla de proyecto y origen altimétrico 285 m","status":"derivado"},{"label":"Volumen geométrico bruto","value":2.208,"unit":"m³","source":"Malla cerrada del elemento","status":"derivado"}],"notes":["Las dimensiones documentadas proceden de anotaciones o cuadros; la caja y el volumen se calculan a partir de la malla.","El volumen es exclusivamente geométrico y bruto; no representa una medición neta de material ni una cantidad de compra."]} | {"documentId":"ARQ-OF-20260710","title":"Planos de arquitectura del edificio de oficinas","date":"2026-07-10","sheet":"Arquitectura A101 / p. 3, A103 / p. 5, A106 / p. 8; A301Cuadro de materiales "} | ["El plano general de 2026-07-31 mantiene el edificio de oficinas de 200 m², mientras documentación anterior indica su supresión. Se conserva lo dibujado, pendiente de confirmación de la propiedad y del equipo de diseño.","Envolvente exterior controlada por la planta de arquitectura; no se han modelado individualmente todas las capas de acabado.","Registro de líneas del PDF general, envolvente de 20 × 10 m; eje local 1 al norte y acceso del lado A al oeste. Estimación de trabajo de implantación de ±0,15 m, pendiente de CAD; no constituye una precisión topográfica garantizada."] | {"horizontalStatus":"derivado","verticalStatus":"derivado","baseElevationM":285.95,"note":"Registro de líneas del PDF general, envolvente de 20 × 10 m; eje local 1 al norte y acceso del lado A al oeste. Estimación de trabajo de implantación de ±0,15 m, pendiente de CAD; no constituye una precisión topográfica garantizada."} | {"Pset_WallCommon":{"IsExternal":{"value":true,"source":"ARQ-OF-20260710 · A101, A103 y alzados; elemento de la envolvente exterior identificada en planta","status":"known"}}} | {"boundingBoxM":{"min":[19.771961,71.769413,2.05],"max":[24.554469,72.621328,4.35]},"extentsM":[4.782508,0.851915,2.3],"meshSurfaceM2":24.919995,"meshVolumeM3":2.207998,"closedSolid":true,"basis":"Geometría triangulada releída del IFC; envolventes y magnitudes no contractuales."} | {"material":true,"document":true,"quantities":true,"containerGuid":"3ztlotcerHPueDgxP84R6z","containerName":"Planta baja"} | {"id":"architecture","name":"Arquitectura"} | {"profileId":"block_masonry","name":"Fábrica de bloques · acabado mineral claro","materialName":"Bloque hueco de hormigón de árido ligero","physicalMaterialStatus":"known","physicalMaterialSource":"ARQ-OF-20260710 · Arquitectura A101 / p. 3, A103 / p. 5, A106 / p. 8; A301Cuadro de materiales ","appearanceStatus":"criterio_visual","appearanceBasis":"Bloque hueco documentado. Apariencia mineral clara para distinguir el cerramiento; no confirma un revoco ni su espesor.","note":"La apariencia gráfica no modifica ni confirma la especificación física del material."} | {"elementId":"office_0205","ifcGuid":"1G_v2pFVnR_xvsoOsd9kZh","ifcClass":"IfcWall","buildingId":"office","buildingName":"Edificio de oficinas","sourceDocumentId":"ARQ-OF-20260710","sourceRepresentationKind":"documentary_mesh"} | {"layerId":"architecture","layerName":"Arquitectura","role":"Muro","basis":"Clasificación por función del elemento; no modifica las especificaciones documentales."} | architecture | {"profileId":"block_masonry","name":"Fábrica de bloques · acabado mineral claro","status":"criterio_visual","basis":"Bloque hueco documentado. Apariencia mineral clara para distinguir el cerramiento; no confirma un revoco ni su espesor.","physicalMaterialUnchanged":true} | ARQ-OF-20260710 · Arquitectura A101 / p. 3, A103 / p. 5, A106 / p. 8; A301Cuadro de materiales | Dimensiones contrastadas con los planos; reconstrucción geométrica a partir de documentación de diseño. | 0.2 | Muros segmentados con huecos reales para puertas y ventanas. | Envolvente exterior controlada por la planta de arquitectura; no se han modelado individualmente todas las capas de acabado. | Registro de líneas del PDF general, envolvente de 20 × 10 m; eje local 1 al norte y acceso del lado A al oeste. Estimación de trabajo de implantación de ±0,15 m, pendiente de CAD; no constituye una precisión topográfica garantizada. | Arquitectura | ARQ-OF-20260710 · Arquitectura A101 / p. 3, A103 / p. 5, A106 / p. 8; A301Cuadro de materiales | 285.95 | Arquitectura | Fábrica de bloques · acabado mineral claro | block_masonry | [0.843137,0.823529,0.772549] | 0.96 | 0 | Bloque hueco documentado. Apariencia mineral clara para distinguir el cerramiento; no confirma un revoco ni su espesor. | Arquitectura; BIM · Arquitectura | El plano general de 2026-07-31 mantiene el edificio de oficinas de 200 m², mientras documentación anterior indica su supresión. Se conserva lo dibujado, pendiente de confirmación de la propiedad y del equipo de diseño.
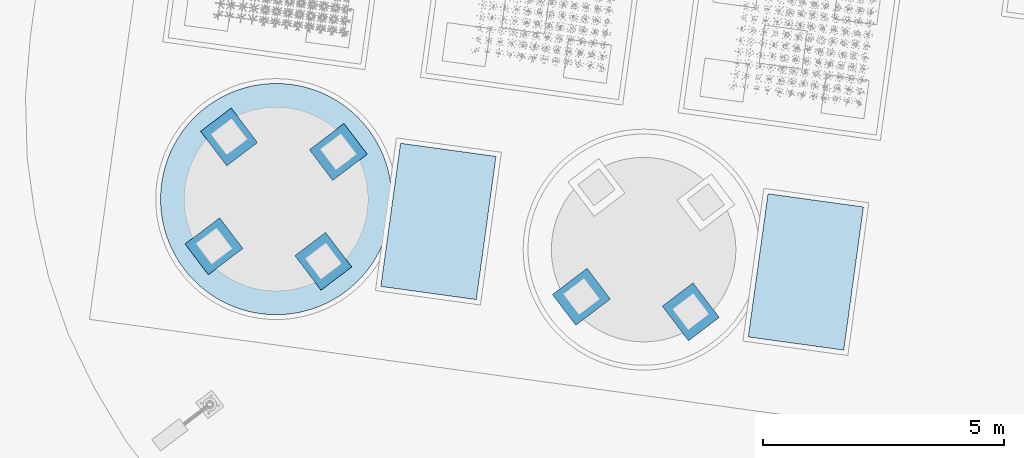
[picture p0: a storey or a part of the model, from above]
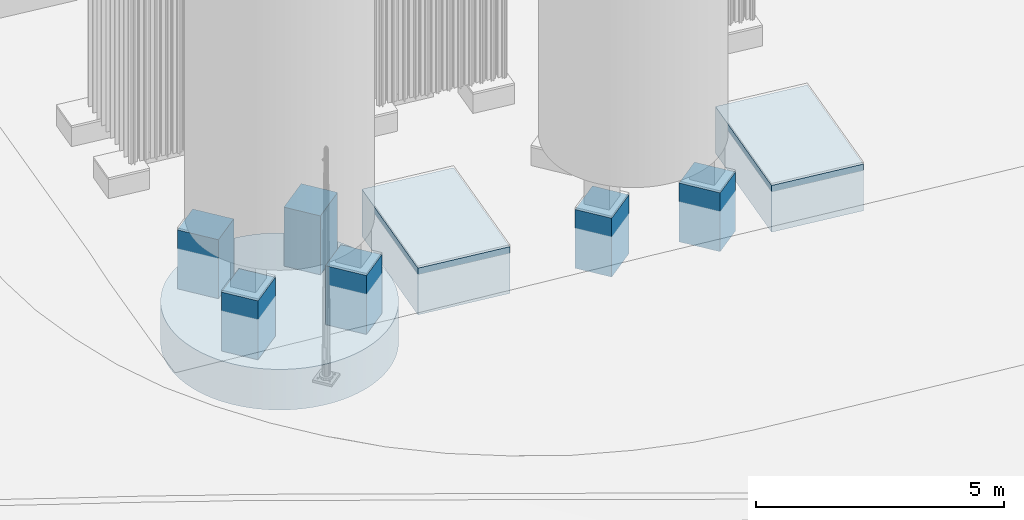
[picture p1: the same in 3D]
Properties of the parts of a building model (IFC4), part 131 of 134

# IfcWall (187)
Name | Document | Material = JH_Trazabilidad, Material = name | Dimensiones de la caja local del elemento (X, Y, Z) | Cota mínima absoluta de la malla (m) | Cota máxima absoluta de la malla (m) | Volumen geométrico bruto (m3) = Volumen geométrico (m³) | Reference = Identificador del elemento = Identificador | IsExternal | ExtensionX (m) | ExtensionY (m) | ExtensionZ (m) | SuperficieDeLaMalla (m2) | VolumenGeometrico (m3) = GrossVolume (m3) | buildingId | buildingName = Edificio | material | dimensions | JH_InformacionBIM, source = DocumentoFuente | issues = IncidenciasPendientes | positioning = PosicionYEstado | commonProperties | geometryMetrics | ifcAssociations | visualLayer | materialAppearance | visualizationIdentity | classification | layerId = IdentificadorCapa | appearance | Planos de referencia | Base geométrica | Espesor del muro (m) = Espesor del muro (m) | Tratamiento de los huecos | Representación de los acabados | Estado de la implantación | Disciplina | Referencia del material = JH_EvidenciaDeMaterial, source | Cota de planta baja terminada (m) | Capa BIM = NombreCapa | Acabado de visualización = Acabado | Perfil | ColorRGB | Rugosidad | Metallicidad | Referencia | Group | Discrepancia entre versiones
Edificio de oficinas · Fábrica de bloques huecos de hormigón de 200 mm · eje 3 · tramo 13 | Planos de arquitectura del edificio de oficinas | Bloque hueco de hormigón de árido ligero | 0.2 × 4.8 × 1.6 | 289.35 | 290.95 | 1.536 | office_0206 | yes | 4.78251 | 0.851915 | 1.6 | 17.92 | 1.536 | office | Edificio de oficinas | {"name":"Bloque hueco de hormigón de árido ligero","source":"ARQ-OF-20260710 · Arquitectura A101 / p. 3, A103 / p. 5, A106 / p. 8; A301Cuadro de materiales ","status":"known"} | {"documented":[{"label":"Espesor del muro","value":0.2,"unit":"m","source":"ARQ-OF-20260710 · Arquitectura A101 / p. 3, A103 / p. 5, A106 / p. 8; A301Cuadro de materiales ","status":"documentado"}],"geometry":[{"label":"Dimensiones de la caja local del elemento (X, Y, Z)","value":"0.2 × 4.8 × 1.6","unit":"m","source":"Malla triangulada del elemento en ejes locales del edificio","status":"derivado"},{"label":"Cota mínima absoluta de la malla","value":289.35,"unit":"m","source":"Malla de proyecto y origen altimétrico 285 m","status":"derivado"},{"label":"Cota máxima absoluta de la malla","value":290.95,"unit":"m","source":"Malla de proyecto y origen altimétrico 285 m","status":"derivado"},{"label":"Volumen geométrico bruto","value":1.536,"unit":"m³","source":"Malla cerrada del elemento","status":"derivado"}],"notes":["Las dimensiones documentadas proceden de anotaciones o cuadros; la caja y el volumen se calculan a partir de la malla.","El volumen es exclusivamente geométrico y bruto; no representa una medición neta de material ni una cantidad de compra."]} | {"documentId":"ARQ-OF-20260710","title":"Planos de arquitectura del edificio de oficinas","date":"2026-07-10","sheet":"Arquitectura A101 / p. 3, A103 / p. 5, A106 / p. 8; A301Cuadro de materiales "} | ["El plano general de 2026-07-31 mantiene el edificio de oficinas de 200 m², mientras documentación anterior indica su supresión. Se conserva lo dibujado, pendiente de confirmación de la propiedad y del equipo de diseño.","Envolvente exterior controlada por la planta de arquitectura; no se han modelado individualmente todas las capas de acabado.","Registro de líneas del PDF general, envolvente de 20 × 10 m; eje local 1 al norte y acceso del lado A al oeste. Estimación de trabajo de implantación de ±0,15 m, pendiente de CAD; no constituye una precisión topográfica garantizada."] | {"horizontalStatus":"derivado","verticalStatus":"derivado","baseElevationM":285.95,"note":"Registro de líneas del PDF general, envolvente de 20 × 10 m; eje local 1 al norte y acceso del lado A al oeste. Estimación de trabajo de implantación de ±0,15 m, pendiente de CAD; no constituye una precisión topográfica garantizada."} | {"Pset_WallCommon":{"IsExternal":{"value":true,"source":"ARQ-OF-20260710 · A101, A103 y alzados; elemento de la envolvente exterior identificada en planta","status":"known"}}} | {"boundingBoxM":{"min":[19.771961,71.769413,4.35],"max":[24.554469,72.621328,5.95]},"extentsM":[4.782508,0.851915,1.6],"meshSurfaceM2":17.919996,"meshVolumeM3":1.535998,"closedSolid":true,"basis":"Geometría triangulada releída del IFC; envolventes y magnitudes no contractuales."} | {"material":true,"document":true,"quantities":true,"containerGuid":"3ztlotcerHPueDgxP84R6z","containerName":"Planta baja"} | {"id":"architecture","name":"Arquitectura"} | {"profileId":"block_masonry","name":"Fábrica de bloques · acabado mineral claro","materialName":"Bloque hueco de hormigón de árido ligero","physicalMaterialStatus":"known","physicalMaterialSource":"ARQ-OF-20260710 · Arquitectura A101 / p. 3, A103 / p. 5, A106 / p. 8; A301Cuadro de materiales ","appearanceStatus":"criterio_visual","appearanceBasis":"Bloque hueco documentado. Apariencia mineral clara para distinguir el cerramiento; no confirma un revoco ni su espesor.","note":"La apariencia gráfica no modifica ni confirma la especificación física del material."} | {"elementId":"office_0206","ifcGuid":"2OMEPi8xDNL8kNYVc3Q1uk","ifcClass":"IfcWall","buildingId":"office","buildingName":"Edificio de oficinas","sourceDocumentId":"ARQ-OF-20260710","sourceRepresentationKind":"documentary_mesh"} | {"layerId":"architecture","layerName":"Arquitectura","role":"Muro","basis":"Clasificación por función del elemento; no modifica las especificaciones documentales."} | architecture | {"profileId":"block_masonry","name":"Fábrica de bloques · acabado mineral claro","status":"criterio_visual","basis":"Bloque hueco documentado. Apariencia mineral clara para distinguir el cerramiento; no confirma un revoco ni su espesor.","physicalMaterialUnchanged":true} | ARQ-OF-20260710 · Arquitectura A101 / p. 3, A103 / p. 5, A106 / p. 8; A301Cuadro de materiales | Dimensiones contrastadas con los planos; reconstrucción geométrica a partir de documentación de diseño. | 0.2 | Muros segmentados con huecos reales para puertas y ventanas. | Envolvente exterior controlada por la planta de arquitectura; no se han modelado individualmente todas las capas de acabado. | Registro de líneas del PDF general, envolvente de 20 × 10 m; eje local 1 al norte y acceso del lado A al oeste. Estimación de trabajo de implantación de ±0,15 m, pendiente de CAD; no constituye una precisión topográfica garantizada. | Arquitectura | ARQ-OF-20260710 · Arquitectura A101 / p. 3, A103 / p. 5, A106 / p. 8; A301Cuadro de materiales | 285.95 | Arquitectura | Fábrica de bloques · acabado mineral claro | block_masonry | [0.843137,0.823529,0.772549] | 0.96 | 0 | Bloque hueco documentado. Apariencia mineral clara para distinguir el cerramiento; no confirma un revoco ni su espesor. | Arquitectura; BIM · Arquitectura | El plano general de 2026-07-31 mantiene el edificio de oficinas de 200 m², mientras documentación anterior indica su supresión. Se conserva lo dibujado, pendiente de confirmación de la propiedad y del equipo de diseño.
Edificio de oficinas · muro de cimentación de 200 mm · eje A | Planos de estructura del edificio de oficinas; Planos de estructura del edificio de oficinas | Hormigón armado | 20 × 0.2 × 1 | 284.95 | 285.95 | 4 | office_0235 |  | 2.92221 | 19.8409 | 1 | 48.4 | 4 | office | Edificio de oficinas | {"name":"Hormigón armado","source":"EST-OF-20260710 · Estructura B201 / p. 5","status":"known"} | {"documented":[{"label":"Espesor","value":0.2,"unit":"m","source":"EST-OF-20260710 · Estructura B201 / p. 5","status":"documentado"},{"label":"Cota inferior absoluta","value":284.95,"unit":"m","source":"EST-OF-20260710 · Estructura B201 / p. 5","status":"documentado"},{"label":"Cota superior absoluta","value":285.95,"unit":"m","source":"EST-OF-20260710 · Estructura B201 / p. 5","status":"documentado"}],"geometry":[{"label":"Dimensiones de la caja local del elemento (X, Y, Z)","value":"20 × 0.2 × 1","unit":"m","source":"Malla triangulada del elemento en ejes locales del edificio","status":"derivado"},{"label":"Cota mínima absoluta de la malla","value":284.95,"unit":"m","source":"Malla de proyecto y origen altimétrico 285 m","status":"derivado"},{"label":"Cota máxima absoluta de la malla","value":285.95,"unit":"m","source":"Malla de proyecto y origen altimétrico 285 m","status":"derivado"},{"label":"Volumen geométrico bruto","value":4.0,"unit":"m³","source":"Malla cerrada del elemento","status":"derivado"}],"notes":["Las dimensiones documentadas proceden de anotaciones o cuadros; la caja y el volumen se calculan a partir de la malla.","El volumen es exclusivamente geométrico y bruto; no representa una medición neta de material ni una cantidad de compra."]} | {"documentId":"EST-OF-20260710","title":"Planos de estructura del edificio de oficinas","date":"2026-07-10","sheet":"Estructura B201 / p. 5"} | ["El plano general de 2026-07-31 mantiene el edificio de oficinas de 200 m², mientras documentación anterior indica su supresión. Se conserva lo dibujado, pendiente de confirmación de la propiedad y del equipo de diseño.","Sistema de ejecución del muro, prefabricado o in situ, pendiente de aclaración.","Registro de líneas del PDF general, envolvente de 20 × 10 m; eje local 1 al norte y acceso del lado A al oeste. Estimación de trabajo de implantación de ±0,15 m, pendiente de CAD; no constituye una precisión topográfica garantizada."] | {"horizontalStatus":"derivado","verticalStatus":"derivado","baseElevationM":285.95,"note":"Registro de líneas del PDF general, envolvente de 20 × 10 m; eje local 1 al norte y acceso del lado A al oeste. Estimación de trabajo de implantación de ±0,15 m, pendiente de CAD; no constituye una precisión topográfica garantizada."} |  | {"boundingBoxM":{"min":[14.818557,73.076971,-0.05],"max":[17.740771,92.917828,0.95]},"extentsM":[2.922214,19.840857,1.0],"meshSurfaceM2":48.399992,"meshVolumeM3":3.999996,"closedSolid":true,"basis":"Geometría triangulada releída del IFC; envolventes y magnitudes no contractuales."} | {"material":true,"document":true,"quantities":true,"containerGuid":"3ztlotcerHPueDgxP84R6z","containerName":"Planta baja"} | {"id":"foundations","name":"Cimentaciones"} | {"profileId":"concrete_reinforced","name":"Hormigón armado · gris natural","materialName":"Hormigón armado","physicalMaterialStatus":"known","physicalMaterialSource":"EST-OF-20260710 · Estructura B201 / p. 5","appearanceStatus":"criterio_visual","appearanceBasis":"Interpretación visual del material documental; el acabado, tono y parámetros PBR no son una especificación contractual.","note":"La apariencia gráfica no modifica ni confirma la especificación física del material."} | {"elementId":"office_0235","ifcGuid":"1Rm2vG5f1RtfWigww$4KMZ","ifcClass":"IfcWall","buildingId":"office","buildingName":"Edificio de oficinas","sourceDocumentId":"EST-OF-20260710","sourceRepresentationKind":"documentary_mesh"} | {"layerId":"foundations","layerName":"Cimentaciones","role":"Muro","basis":"Clasificación por función del elemento; no modifica las especificaciones documentales."} | foundations | {"profileId":"concrete_reinforced","name":"Hormigón armado · gris natural","status":"criterio_visual","basis":"Interpretación visual del material documental; el acabado, tono y parámetros PBR no son una especificación contractual.","physicalMaterialUnchanged":true} | EST-OF-20260710 · Estructura B201 / p. 5 | Espesor de 200 mm y cotas inferior y superior según las secciones; posición en planta simplificada siguiendo el cerramiento exterior. |  |  |  | Registro de líneas del PDF general, envolvente de 20 × 10 m; eje local 1 al norte y acceso del lado A al oeste. Estimación de trabajo de implantación de ±0,15 m, pendiente de CAD; no constituye una precisión topográfica garantizada. | Cimentación | EST-OF-20260710 · Estructura B201 / p. 5 | 285.95 | Cimentaciones | Hormigón armado · gris natural | concrete_reinforced | [0.666667,0.662745,0.619608] | 0.96 | 0 | Interpretación visual del material documental; el acabado, tono y parámetros PBR no son una especificación contractual. | Cimentación; BIM · Cimentaciones | El plano general de 2026-07-31 mantiene el edificio de oficinas de 200 m², mientras documentación anterior indica su supresión. Se conserva lo dibujado, pendiente de confirmación de la propiedad y del equipo de diseño. | JH_Trazabilidad - Espesor (m): 0.2; Cota inferior absoluta (m): 284.95; Cota superior absoluta (m): 285.95; Hormigón: Muro de hormigón; terminología de prefabricación y hormigonado in situ pendiente de aclaración.; JH_DimensionesDocumentadas - Espesor: 0.2 m; Cota inferior absoluta: 284.95 m; Cota superior absoluta: 285.95 m
Edificio de oficinas · muro de cimentación de 200 mm · eje B | Planos de estructura del edificio de oficinas; Planos de estructura del edificio de oficinas | Hormigón armado | 20 × 0.2 × 1 | 284.95 | 285.95 | 4 | office_0236 |  | 2.92221 | 19.8409 | 1 | 48.4 | 4 | office | Edificio de oficinas | {"name":"Hormigón armado","source":"EST-OF-20260710 · Estructura B201 / p. 5","status":"known"} | {"documented":[{"label":"Espesor","value":0.2,"unit":"m","source":"EST-OF-20260710 · Estructura B201 / p. 5","status":"documentado"},{"label":"Cota inferior absoluta","value":284.95,"unit":"m","source":"EST-OF-20260710 · Estructura B201 / p. 5","status":"documentado"},{"label":"Cota superior absoluta","value":285.95,"unit":"m","source":"EST-OF-20260710 · Estructura B201 / p. 5","status":"documentado"}],"geometry":[{"label":"Dimensiones de la caja local del elemento (X, Y, Z)","value":"20 × 0.2 × 1","unit":"m","source":"Malla triangulada del elemento en ejes locales del edificio","status":"derivado"},{"label":"Cota mínima absoluta de la malla","value":284.95,"unit":"m","source":"Malla de proyecto y origen altimétrico 285 m","status":"derivado"},{"label":"Cota máxima absoluta de la malla","value":285.95,"unit":"m","source":"Malla de proyecto y origen altimétrico 285 m","status":"derivado"},{"label":"Volumen geométrico bruto","value":4.0,"unit":"m³","source":"Malla cerrada del elemento","status":"derivado"}],"notes":["Las dimensiones documentadas proceden de anotaciones o cuadros; la caja y el volumen se calculan a partir de la malla.","El volumen es exclusivamente geométrico y bruto; no representa una medición neta de material ni una cantidad de compra."]} | {"documentId":"EST-OF-20260710","title":"Planos de estructura del edificio de oficinas","date":"2026-07-10","sheet":"Estructura B201 / p. 5"} | ["El plano general de 2026-07-31 mantiene el edificio de oficinas de 200 m², mientras documentación anterior indica su supresión. Se conserva lo dibujado, pendiente de confirmación de la propiedad y del equipo de diseño.","Sistema de ejecución del muro, prefabricado o in situ, pendiente de aclaración.","Registro de líneas del PDF general, envolvente de 20 × 10 m; eje local 1 al norte y acceso del lado A al oeste. Estimación de trabajo de implantación de ±0,15 m, pendiente de CAD; no constituye una precisión topográfica garantizada."] | {"horizontalStatus":"derivado","verticalStatus":"derivado","baseElevationM":285.95,"note":"Registro de líneas del PDF general, envolvente de 20 × 10 m; eje local 1 al norte y acceso del lado A al oeste. Estimación de trabajo de implantación de ±0,15 m, pendiente de CAD; no constituye una precisión topográfica garantizada."} |  | {"boundingBoxM":{"min":[24.527229,71.742172,-0.05],"max":[27.449443,91.583029,0.95]},"extentsM":[2.922214,19.840857,1.0],"meshSurfaceM2":48.399992,"meshVolumeM3":3.999996,"closedSolid":true,"basis":"Geometría triangulada releída del IFC; envolventes y magnitudes no contractuales."} | {"material":true,"document":true,"quantities":true,"containerGuid":"3ztlotcerHPueDgxP84R6z","containerName":"Planta baja"} | {"id":"foundations","name":"Cimentaciones"} | {"profileId":"concrete_reinforced","name":"Hormigón armado · gris natural","materialName":"Hormigón armado","physicalMaterialStatus":"known","physicalMaterialSource":"EST-OF-20260710 · Estructura B201 / p. 5","appearanceStatus":"criterio_visual","appearanceBasis":"Interpretación visual del material documental; el acabado, tono y parámetros PBR no son una especificación contractual.","note":"La apariencia gráfica no modifica ni confirma la especificación física del material."} | {"elementId":"office_0236","ifcGuid":"2ntkaB1kLNi9caoySVpUOv","ifcClass":"IfcWall","buildingId":"office","buildingName":"Edificio de oficinas","sourceDocumentId":"EST-OF-20260710","sourceRepresentationKind":"documentary_mesh"} | {"layerId":"foundations","layerName":"Cimentaciones","role":"Muro","basis":"Clasificación por función del elemento; no modifica las especificaciones documentales."} | foundations | {"profileId":"concrete_reinforced","name":"Hormigón armado · gris natural","status":"criterio_visual","basis":"Interpretación visual del material documental; el acabado, tono y parámetros PBR no son una especificación contractual.","physicalMaterialUnchanged":true} | EST-OF-20260710 · Estructura B201 / p. 5 | Espesor de 200 mm y cotas inferior y superior según las secciones; posición en planta simplificada siguiendo el cerramiento exterior. |  |  |  | Registro de líneas del PDF general, envolvente de 20 × 10 m; eje local 1 al norte y acceso del lado A al oeste. Estimación de trabajo de implantación de ±0,15 m, pendiente de CAD; no constituye una precisión topográfica garantizada. | Cimentación | EST-OF-20260710 · Estructura B201 / p. 5 | 285.95 | Cimentaciones | Hormigón armado · gris natural | concrete_reinforced | [0.666667,0.662745,0.619608] | 0.96 | 0 | Interpretación visual del material documental; el acabado, tono y parámetros PBR no son una especificación contractual. | Cimentación; BIM · Cimentaciones | El plano general de 2026-07-31 mantiene el edificio de oficinas de 200 m², mientras documentación anterior indica su supresión. Se conserva lo dibujado, pendiente de confirmación de la propiedad y del equipo de diseño. | JH_Trazabilidad - Espesor (m): 0.2; Cota inferior absoluta (m): 284.95; Cota superior absoluta (m): 285.95; Hormigón: Muro de hormigón; terminología de prefabricación y hormigonado in situ pendiente de aclaración.; JH_DimensionesDocumentadas - Espesor: 0.2 m; Cota inferior absoluta: 284.95 m; Cota superior absoluta: 285.95 m
Edificio de oficinas · muro de cimentación de 200 mm · eje 1 | Planos de estructura del edificio de oficinas; Planos de estructura del edificio de oficinas | Hormigón armado | 0.2 × 9.6 × 1 | 284.95 | 285.95 | 1.92 | office_0237 |  | 9.53778 | 1.50569 | 1 | 23.44 | 1.92 | office | Edificio de oficinas | {"name":"Hormigón armado","source":"EST-OF-20260710 · Estructura B201 / p. 5","status":"known"} | {"documented":[{"label":"Espesor","value":0.2,"unit":"m","source":"EST-OF-20260710 · Estructura B201 / p. 5","status":"documentado"},{"label":"Cota inferior absoluta","value":284.95,"unit":"m","source":"EST-OF-20260710 · Estructura B201 / p. 5","status":"documentado"},{"label":"Cota superior absoluta","value":285.95,"unit":"m","source":"EST-OF-20260710 · Estructura B201 / p. 5","status":"documentado"}],"geometry":[{"label":"Dimensiones de la caja local del elemento (X, Y, Z)","value":"0.2 × 9.6 × 1","unit":"m","source":"Malla triangulada del elemento en ejes locales del edificio","status":"derivado"},{"label":"Cota mínima absoluta de la malla","value":284.95,"unit":"m","source":"Malla de proyecto y origen altimétrico 285 m","status":"derivado"},{"label":"Cota máxima absoluta de la malla","value":285.95,"unit":"m","source":"Malla de proyecto y origen altimétrico 285 m","status":"derivado"},{"label":"Volumen geométrico bruto","value":1.92,"unit":"m³","source":"Malla cerrada del elemento","status":"derivado"}],"notes":["Las dimensiones documentadas proceden de anotaciones o cuadros; la caja y el volumen se calculan a partir de la malla.","El volumen es exclusivamente geométrico y bruto; no representa una medición neta de material ni una cantidad de compra."]} | {"documentId":"EST-OF-20260710","title":"Planos de estructura del edificio de oficinas","date":"2026-07-10","sheet":"Estructura B201 / p. 5"} | ["El plano general de 2026-07-31 mantiene el edificio de oficinas de 200 m², mientras documentación anterior indica su supresión. Se conserva lo dibujado, pendiente de confirmación de la propiedad y del equipo de diseño.","Sistema de ejecución del muro, prefabricado o in situ, pendiente de aclaración.","Registro de líneas del PDF general, envolvente de 20 × 10 m; eje local 1 al norte y acceso del lado A al oeste. Estimación de trabajo de implantación de ±0,15 m, pendiente de CAD; no constituye una precisión topográfica garantizada."] | {"horizontalStatus":"derivado","verticalStatus":"derivado","baseElevationM":285.95,"note":"Registro de líneas del PDF general, envolvente de 20 × 10 m; eje local 1 al norte y acceso del lado A al oeste. Estimación de trabajo de implantación de ±0,15 m, pendiente de CAD; no constituye una precisión topográfica garantizada."} |  | {"boundingBoxM":{"min":[17.713531,91.384893,-0.05],"max":[27.251307,92.890587,0.95]},"extentsM":[9.537776,1.505694,1.0],"meshSurfaceM2":23.439995,"meshVolumeM3":1.919998,"closedSolid":true,"basis":"Geometría triangulada releída del IFC; envolventes y magnitudes no contractuales."} | {"material":true,"document":true,"quantities":true,"containerGuid":"3ztlotcerHPueDgxP84R6z","containerName":"Planta baja"} | {"id":"foundations","name":"Cimentaciones"} | {"profileId":"concrete_reinforced","name":"Hormigón armado · gris natural","materialName":"Hormigón armado","physicalMaterialStatus":"known","physicalMaterialSource":"EST-OF-20260710 · Estructura B201 / p. 5","appearanceStatus":"criterio_visual","appearanceBasis":"Interpretación visual del material documental; el acabado, tono y parámetros PBR no son una especificación contractual.","note":"La apariencia gráfica no modifica ni confirma la especificación física del material."} | {"elementId":"office_0237","ifcGuid":"0MDXa97YTJJwGmfeKcaBJ4","ifcClass":"IfcWall","buildingId":"office","buildingName":"Edificio de oficinas","sourceDocumentId":"EST-OF-20260710","sourceRepresentationKind":"documentary_mesh"} | {"layerId":"foundations","layerName":"Cimentaciones","role":"Muro","basis":"Clasificación por función del elemento; no modifica las especificaciones documentales."} | foundations | {"profileId":"concrete_reinforced","name":"Hormigón armado · gris natural","status":"criterio_visual","basis":"Interpretación visual del material documental; el acabado, tono y parámetros PBR no son una especificación contractual.","physicalMaterialUnchanged":true} | EST-OF-20260710 · Estructura B201 / p. 5 | Espesor de 200 mm y cotas inferior y superior según las secciones; posición en planta simplificada siguiendo el cerramiento exterior. |  |  |  | Registro de líneas del PDF general, envolvente de 20 × 10 m; eje local 1 al norte y acceso del lado A al oeste. Estimación de trabajo de implantación de ±0,15 m, pendiente de CAD; no constituye una precisión topográfica garantizada. | Cimentación | EST-OF-20260710 · Estructura B201 / p. 5 | 285.95 | Cimentaciones | Hormigón armado · gris natural | concrete_reinforced | [0.666667,0.662745,0.619608] | 0.96 | 0 | Interpretación visual del material documental; el acabado, tono y parámetros PBR no son una especificación contractual. | Cimentación; BIM · Cimentaciones | El plano general de 2026-07-31 mantiene el edificio de oficinas de 200 m², mientras documentación anterior indica su supresión. Se conserva lo dibujado, pendiente de confirmación de la propiedad y del equipo de diseño. | JH_Trazabilidad - Espesor (m): 0.2; Cota inferior absoluta (m): 284.95; Cota superior absoluta (m): 285.95; Hormigón: Muro de hormigón; terminología de prefabricación y hormigonado in situ pendiente de aclaración.; JH_DimensionesDocumentadas - Espesor: 0.2 m; Cota inferior absoluta: 284.95 m; Cota superior absoluta: 285.95 m
Edificio de oficinas · muro de cimentación de 200 mm · eje 3 | Planos de estructura del edificio de oficinas; Planos de estructura del edificio de oficinas | Hormigón armado | 0.2 × 9.6 × 1 | 284.95 | 285.95 | 1.92 | office_0238 |  | 9.53778 | 1.50569 | 1 | 23.44 | 1.92 | office | Edificio de oficinas | {"name":"Hormigón armado","source":"EST-OF-20260710 · Estructura B201 / p. 5","status":"known"} | {"documented":[{"label":"Espesor","value":0.2,"unit":"m","source":"EST-OF-20260710 · Estructura B201 / p. 5","status":"documentado"},{"label":"Cota inferior absoluta","value":284.95,"unit":"m","source":"EST-OF-20260710 · Estructura B201 / p. 5","status":"documentado"},{"label":"Cota superior absoluta","value":285.95,"unit":"m","source":"EST-OF-20260710 · Estructura B201 / p. 5","status":"documentado"}],"geometry":[{"label":"Dimensiones de la caja local del elemento (X, Y, Z)","value":"0.2 × 9.6 × 1","unit":"m","source":"Malla triangulada del elemento en ejes locales del edificio","status":"derivado"},{"label":"Cota mínima absoluta de la malla","value":284.95,"unit":"m","source":"Malla de proyecto y origen altimétrico 285 m","status":"derivado"},{"label":"Cota máxima absoluta de la malla","value":285.95,"unit":"m","source":"Malla de proyecto y origen altimétrico 285 m","status":"derivado"},{"label":"Volumen geométrico bruto","value":1.92,"unit":"m³","source":"Malla cerrada del elemento","status":"derivado"}],"notes":["Las dimensiones documentadas proceden de anotaciones o cuadros; la caja y el volumen se calculan a partir de la malla.","El volumen es exclusivamente geométrico y bruto; no representa una medición neta de material ni una cantidad de compra."]} | {"documentId":"EST-OF-20260710","title":"Planos de estructura del edificio de oficinas","date":"2026-07-10","sheet":"Estructura B201 / p. 5"} | ["El plano general de 2026-07-31 mantiene el edificio de oficinas de 200 m², mientras documentación anterior indica su supresión. Se conserva lo dibujado, pendiente de confirmación de la propiedad y del equipo de diseño.","Sistema de ejecución del muro, prefabricado o in situ, pendiente de aclaración.","Registro de líneas del PDF general, envolvente de 20 × 10 m; eje local 1 al norte y acceso del lado A al oeste. Estimación de trabajo de implantación de ±0,15 m, pendiente de CAD; no constituye una precisión topográfica garantizada."] | {"horizontalStatus":"derivado","verticalStatus":"derivado","baseElevationM":285.95,"note":"Registro de líneas del PDF general, envolvente de 20 × 10 m; eje local 1 al norte y acceso del lado A al oeste. Estimación de trabajo de implantación de ±0,15 m, pendiente de CAD; no constituye una precisión topográfica garantizada."} |  | {"boundingBoxM":{"min":[15.016693,71.769413,-0.05],"max":[24.554469,73.275107,0.95]},"extentsM":[9.537776,1.505694,1.0],"meshSurfaceM2":23.439995,"meshVolumeM3":1.919998,"closedSolid":true,"basis":"Geometría triangulada releída del IFC; envolventes y magnitudes no contractuales."} | {"material":true,"document":true,"quantities":true,"containerGuid":"3ztlotcerHPueDgxP84R6z","containerName":"Planta baja"} | {"id":"foundations","name":"Cimentaciones"} | {"profileId":"concrete_reinforced","name":"Hormigón armado · gris natural","materialName":"Hormigón armado","physicalMaterialStatus":"known","physicalMaterialSource":"EST-OF-20260710 · Estructura B201 / p. 5","appearanceStatus":"criterio_visual","appearanceBasis":"Interpretación visual del material documental; el acabado, tono y parámetros PBR no son una especificación contractual.","note":"La apariencia gráfica no modifica ni confirma la especificación física del material."} | {"elementId":"office_0238","ifcGuid":"038JI0PzfMGOgT_kF1sY1S","ifcClass":"IfcWall","buildingId":"office","buildingName":"Edificio de oficinas","sourceDocumentId":"EST-OF-20260710","sourceRepresentationKind":"documentary_mesh"} | {"layerId":"foundations","layerName":"Cimentaciones","role":"Muro","basis":"Clasificación por función del elemento; no modifica las especificaciones documentales."} | foundations | {"profileId":"concrete_reinforced","name":"Hormigón armado · gris natural","status":"criterio_visual","basis":"Interpretación visual del material documental; el acabado, tono y parámetros PBR no son una especificación contractual.","physicalMaterialUnchanged":true} | EST-OF-20260710 · Estructura B201 / p. 5 | Espesor de 200 mm y cotas inferior y superior según las secciones; posición en planta simplificada siguiendo el cerramiento exterior. |  |  |  | Registro de líneas del PDF general, envolvente de 20 × 10 m; eje local 1 al norte y acceso del lado A al oeste. Estimación de trabajo de implantación de ±0,15 m, pendiente de CAD; no constituye una precisión topográfica garantizada. | Cimentación | EST-OF-20260710 · Estructura B201 / p. 5 | 285.95 | Cimentaciones | Hormigón armado · gris natural | concrete_reinforced | [0.666667,0.662745,0.619608] | 0.96 | 0 | Interpretación visual del material documental; el acabado, tono y parámetros PBR no son una especificación contractual. | Cimentación; BIM · Cimentaciones | El plano general de 2026-07-31 mantiene el edificio de oficinas de 200 m², mientras documentación anterior indica su supresión. Se conserva lo dibujado, pendiente de confirmación de la propiedad y del equipo de diseño. | JH_Trazabilidad - Espesor (m): 0.2; Cota inferior absoluta (m): 284.95; Cota superior absoluta (m): 285.95; Hormigón: Muro de hormigón; terminología de prefabricación y hormigonado in situ pendiente de aclaración.; JH_DimensionesDocumentadas - Espesor: 0.2 m; Cota inferior absoluta: 284.95 m; Cota superior absoluta: 285.95 m

# IfcWall: Fábrica MU10 con mortero M7.5 y revestimiento de granito (2)
In: Parcela industrial Jinhong
Description: Modelo de coordinación a partir de planos. Las dimensiones documentadas se separan de las simplificaciones gráficas y cotas de terreno interpoladas; no son cantidades certificadas de obra.; PredefinedType: USERDEFINED; Document: Detalles del vallado perimetral · paquete emitido 31/07/2026; Ubicación de muros perimetrales · CAD original; Implantación y rasantes de la parcela; Group: BIM · Vallado perimetral
JH_InformacionBIM - buildingId: site; buildingName: Urbanización y parcela; level: Exterior · vallado perimetral; category: Fábrica MU10 con mortero M7.5 y revestimiento de granito; ifcClass: IfcWall; status: derivado; source: {"documentId":"JH-U010-20260731","title":"Detalles del vallado perimetral · paquete emitido 31/07/2026","sheet":"U010 · página 11 del PDF original","date":"2026-07-10","issueDate":"2026-07-31","note":"Fecha del cajetín 10/07/2026; último paquete disponible de esta especialidad emitido 31/07/2026."}; planSource: {"documentId":"JH-U009-20260731","title":"Ubicación de muros perimetrales · CAD original","sheet":"U009 · página 10 del PDF original","date":"2026-07-10","issueDate":"2026-07-31"}; material: {"name":"Fábrica MU10 con mortero M7.5 y revestimiento de granito","status":"documentado","source":"U010 · detalle del vallado / acceso"}; appearance: {"profileId":"fence_granite","name":"Granito gris del acceso","status":"criterio_visual","basis":"U010: granito gris de sésamo, acabado flameado. Se representa el acabado externo sin simular el despiece de placas."}; visualLayer: {"id":"fences","name":"Vallado perimetral","defaultVisible":true}; representationKind: geometria_derivada_de_planos; terrainBasis: Apoyo coordinado con la superficie de urbanización ya representada; interpolación sobre sus triángulos, con proyección al borde próximo cuando el eje queda fuera. No constituye rasante de ejecución. Datum absoluto pendiente de confirmación.; positioning: {"Trazado":"Coordenadas originales del DWG, ETRS89 / UTM 29N, origen local 729400 / 4301550 m","Apoyo":"Apoyo coordinado con la superficie de urbanización ya representada; interpolación sobre sus triángulos, con proyección al borde próximo cuando el eje queda fuera. No constituye rasante de ejecución. Datum absoluto pendiente de confirmación."}; issues: ["U010 indica 286,10 m en el vértice noreste y U004 288,00 m. En el vértice noroeste U010 indica 286,65 y 285,65 m, frente a 285,70 m de U004. Se conservan las alturas relativas del detalle; las cotas absolutas requieren coordinación.","U010 acota 0,05 m por cara, pero las capas descritas suman 0,04 m. No se inventa una capa adicional.","El muro largo mide aproximadamente 0,514 m de ancho en CAD frente a 0,500 m nominales; se conserva su polígono de implantación."]; quantityEligible: no
JH_Trazabilidad - Documento de origen: U009 / U010 · paquete 31/07/2026 · cajetín 10/07/2026; Capa BIM: Vallado perimetral; Aplicabilidad a mediciones: Geometría de coordinación; no usar como cantidades certificadas.; Categoria: Fábrica MU10 con mortero M7.5 y revestimiento de granito; ClaseIFC: IfcWall; EstadoDeInformacion: derivado; DocumentoFuente: {"documentId":"JH-U010-20260731","title":"Detalles del vallado perimetral · paquete emitido 31/07/2026","sheet":"U010 · página 11 del PDF original","date":"2026-07-10","issueDate":"2026-07-31","note":"Fecha del cajetín 10/07/2026; último paquete disponible de esta especialidad emitido 31/07/2026."}; IncidenciasPendientes: ["U010 indica 286,10 m en el vértice noreste y U004 288,00 m. En el vértice noroeste U010 indica 286,65 y 285,65 m, frente a 285,70 m de U004. Se conservan las alturas relativas del detalle; las cotas absolutas requieren coordinación.","U010 acota 0,05 m por cara, pero las capas descritas suman 0,04 m. No se inventa una capa adicional.","El muro largo mide aproximadamente 0,514 m de ancho en CAD frente a 0,500 m nominales; se conserva su polígono de implantación."]; UsoDeLasMagnitudes: Modelo de coordinación a partir de planos. Las dimensiones documentadas se separan de las simplificaciones gráficas y cotas de terreno interpoladas; no son cantidades certificadas de obra.
JH_CriterioDePosicion - PosicionYEstado: {"Trazado":"Coordenadas originales del DWG, ETRS89 / UTM 29N, origen local 729400 / 4301550 m","Apoyo":"Apoyo coordinado con la superficie de urbanización ya representada; interpolación sobre sus triángulos, con proyección al borde próximo cuando el eje queda fuera. No constituye rasante de ejecución. Datum absoluto pendiente de confirmación."}
JH_EvidenciaDeMaterial - name: Fábrica MU10 con mortero M7.5 y revestimiento de granito; status: documentado; source: U010 · detalle del vallado / acceso
JH_DimensionesDocumentadas - Espesor nominal terminado: 0.5 m; Altura terminada: 1.95 m; Núcleo de fábrica: 0.4 m; Piedra de granito: 20; Mortero de asiento: 20
JH_CapaBIM - IdentificadorCapa: fences; NombreCapa: Vallado perimetral; Funcion: Fábrica MU10 con mortero M7.5 y revestimiento de granito; VisibilidadInicial: yes
JH_Vallado - PlanoDeImplantacion: {"documentId":"JH-U009-20260731","title":"Ubicación de muros perimetrales · CAD original","sheet":"U009 · página 10 del PDF original","date":"2026-07-10","issueDate":"2026-07-31"}; NivelDelTerreno: Apoyo coordinado con la superficie de urbanización ya representada; interpolación sobre sus triángulos, con proyección al borde próximo cuando el eje queda fuera. No constituye rasante de ejecución. Datum absoluto pendiente de confirmación.; Simplificaciones: [{"label":"Representación","value":"Envolvente exterior sobre polígono CAD. No se modelan la cimentación, las capas interiores ni el despiece de placas","unit":""}]; IncluirEnMediciones: no
JH_AcabadoVisual - Perfil: fence_granite; Acabado: Granito gris del acceso; ColorRGB: [0.56,0.57,0.56]; Rugosidad: 0.8; Metallicidad: 0; Estado: criterio_visual; Referencia: U010: granito gris de sésamo, acabado flameado. Se representa el acabado externo sin simular el despiece de placas.
Name | dimensions | classification | fenceSegmentId = Trazado CAD = Tramo | fenceBasis = Criterio | geometryMetrics | Identificador | Longitud nominal terminada (m)
Muro de acceso largo · granito gris | {"documented":[{"label":"Longitud nominal terminada","value":7.5,"unit":"m"},{"label":"Espesor nominal terminado","value":0.5,"unit":"m"},{"label":"Altura terminada","value":1.95,"unit":"m"},{"label":"Núcleo de fábrica","value":0.4,"unit":"m"},{"label":"Piedra de granito","value":20,"unit":"mm"},{"label":"Mortero de asiento","value":20,"unit":"mm"}],"assumed":[{"label":"Representación","value":"Envolvente exterior sobre polígono CAD. No se modelan la cimentación, las capas interiores ni el despiece de placas","unit":""}],"geometry":[{"label":"Extensión representada X","value":1.16387,"unit":"m"},{"label":"Extensión representada Y","value":7.515843,"unit":"m"},{"label":"Extensión representada Z","value":1.974972,"unit":"m"}]} | {"layerId":"fences","layerName":"Vallado perimetral","function":"Muro de acceso largo · granito gris"} | 21B18 | Polígono cerrado original 21B18; longitud y altura nominales de U010. Se conserva libre el acceso de 7,50 m. | {"boundingBoxM":{"min":[-1.313816,93.41803,0.688548],"max":[-0.149946,100.933873,2.66352]},"extentsM":[1.16387,7.515843,1.974972],"meshSurfaceM2":38.972704,"meshVolumeM3":7.524536,"closedSolid":true,"basis":"Modelo de coordinación a partir de planos. Las dimensiones documentadas se separan de las simplificaciones gráficas y cotas de terreno interpoladas; no son cantidades certificadas de obra."} | FENCE-ENTRANCE-21B18 | 7.5
Muro de acceso corto · granito gris | {"documented":[{"label":"Longitud nominal terminada","value":1.0,"unit":"m"},{"label":"Espesor nominal terminado","value":0.5,"unit":"m"},{"label":"Altura terminada","value":1.95,"unit":"m"},{"label":"Núcleo de fábrica","value":0.4,"unit":"m"},{"label":"Piedra de granito","value":20,"unit":"mm"},{"label":"Mortero de asiento","value":20,"unit":"mm"}],"assumed":[{"label":"Representación","value":"Envolvente exterior sobre polígono CAD. No se modelan la cimentación, las capas interiores ni el despiece de placas","unit":""}],"geometry":[{"label":"Extensión representada X","value":0.583905,"unit":"m"},{"label":"Extensión representada Y","value":1.039439,"unit":"m"},{"label":"Extensión representada Z","value":1.95,"unit":"m"}]} | {"layerId":"fences","layerName":"Vallado perimetral","function":"Muro de acceso corto · granito gris"} | 21B19 | Polígono cerrado original 21B19; longitud y altura nominales de U010. Se conserva libre el acceso de 7,50 m. | {"boundingBoxM":{"min":[0.011095,108.360777,0.694078],"max":[0.595,109.400216,2.644078]},"extentsM":[0.583905,1.039439,1.95],"meshSurfaceM2":6.843794,"meshVolumeM3":0.972949,"closedSolid":true,"basis":"Modelo de coordinación a partir de planos. Las dimensiones documentadas se separan de las simplificaciones gráficas y cotas de terreno interpoladas; no son cantidades certificadas de obra."} | FENCE-ENTRANCE-21B19 | 1

# IfcWall: Hormigón prefabricado (6)
In: Parcela industrial Jinhong
Description: Modelo de coordinación a partir de planos. Las dimensiones documentadas se separan de las simplificaciones gráficas y cotas de terreno interpoladas; no son cantidades certificadas de obra.; PredefinedType: USERDEFINED; Document: Detalles del vallado perimetral · paquete emitido 31/07/2026; Ubicación de muros perimetrales · CAD original; Implantación y rasantes de la parcela; Group: BIM · Vallado perimetral
JH_InformacionBIM - buildingId: site; buildingName: Urbanización y parcela; level: Exterior · vallado perimetral; category: Hormigón prefabricado; ifcClass: IfcWall; status: derivado; source: {"documentId":"JH-U010-20260731","title":"Detalles del vallado perimetral · paquete emitido 31/07/2026","sheet":"U010 · página 11 del PDF original","date":"2026-07-10","issueDate":"2026-07-31","note":"Fecha del cajetín 10/07/2026; último paquete disponible de esta especialidad emitido 31/07/2026."}; planSource: {"documentId":"JH-U009-20260731","title":"Ubicación de muros perimetrales · CAD original","sheet":"U009 · página 10 del PDF original","date":"2026-07-10","issueDate":"2026-07-31"}; material: {"name":"Hormigón prefabricado","status":"documentado","source":"U010 · detalle del vallado / acceso"}; appearance: {"profileId":"fence_concrete","name":"Basamento de hormigón prefabricado","status":"criterio_visual","basis":"Material indicado en U010. Tono y rugosidad adoptados para visualización."}; visualLayer: {"id":"fences","name":"Vallado perimetral","defaultVisible":true}; representationKind: geometria_derivada_de_planos; fenceBasis: Ejes y polígonos del CAD U009; alturas y materiales de U010. Las aberturas de acceso se mantienen libres.; terrainBasis: Apoyo coordinado con la superficie de urbanización ya representada; interpolación sobre sus triángulos, con proyección al borde próximo cuando el eje queda fuera. No constituye rasante de ejecución. Datum absoluto pendiente de confirmación.; positioning: {"Trazado":"Coordenadas originales del DWG, ETRS89 / UTM 29N, origen local 729400 / 4301550 m","Apoyo":"Apoyo coordinado con la superficie de urbanización ya representada; interpolación sobre sus triángulos, con proyección al borde próximo cuando el eje queda fuera. No constituye rasante de ejecución. Datum absoluto pendiente de confirmación."}; issues: ["U010 indica 286,10 m en el vértice noreste y U004 288,00 m. En el vértice noroeste U010 indica 286,65 y 285,65 m, frente a 285,70 m de U004. Se conservan las alturas relativas del detalle; las cotas absolutas requieren coordinación.","Las juntas, anclajes, armaduras, transición escalonada exacta y ejecución sobre pendientes no se consideran definidos por esta malla."]; quantityEligible: no
JH_Trazabilidad - Documento de origen: U009 / U010 · paquete 31/07/2026 · cajetín 10/07/2026; Capa BIM: Vallado perimetral; Aplicabilidad a mediciones: Geometría de coordinación; no usar como cantidades certificadas.; Categoria: Hormigón prefabricado; ClaseIFC: IfcWall; EstadoDeInformacion: derivado; DocumentoFuente: {"documentId":"JH-U010-20260731","title":"Detalles del vallado perimetral · paquete emitido 31/07/2026","sheet":"U010 · página 11 del PDF original","date":"2026-07-10","issueDate":"2026-07-31","note":"Fecha del cajetín 10/07/2026; último paquete disponible de esta especialidad emitido 31/07/2026."}; IncidenciasPendientes: ["U010 indica 286,10 m en el vértice noreste y U004 288,00 m. En el vértice noroeste U010 indica 286,65 y 285,65 m, frente a 285,70 m de U004. Se conservan las alturas relativas del detalle; las cotas absolutas requieren coordinación.","Las juntas, anclajes, armaduras, transición escalonada exacta y ejecución sobre pendientes no se consideran definidos por esta malla."]; UsoDeLasMagnitudes: Modelo de coordinación a partir de planos. Las dimensiones documentadas se separan de las simplificaciones gráficas y cotas de terreno interpoladas; no son cantidades certificadas de obra.
JH_CriterioDePosicion - PosicionYEstado: {"Trazado":"Coordenadas originales del DWG, ETRS89 / UTM 29N, origen local 729400 / 4301550 m","Apoyo":"Apoyo coordinado con la superficie de urbanización ya representada; interpolación sobre sus triángulos, con proyección al borde próximo cuando el eje queda fuera. No constituye rasante de ejecución. Datum absoluto pendiente de confirmación."}
JH_EvidenciaDeMaterial - name: Hormigón prefabricado; status: documentado; source: U010 · detalle del vallado / acceso
JH_DimensionesDocumentadas - Altura sobre terreno: 0.5 m; Profundidad bajo terreno: 0.5 m; Ancho inferior: 0.4 m; Ancho superior: 0.2 m
JH_CapaBIM - IdentificadorCapa: fences; NombreCapa: Vallado perimetral; Funcion: Hormigón prefabricado; VisibilidadInicial: yes
JH_Vallado - Criterio: Ejes y polígonos del CAD U009; alturas y materiales de U010. Las aberturas de acceso se mantienen libres.; PlanoDeImplantacion: {"documentId":"JH-U009-20260731","title":"Ubicación de muros perimetrales · CAD original","sheet":"U009 · página 10 del PDF original","date":"2026-07-10","issueDate":"2026-07-31"}; NivelDelTerreno: Apoyo coordinado con la superficie de urbanización ya representada; interpolación sobre sus triángulos, con proyección al borde próximo cuando el eje queda fuera. No constituye rasante de ejecución. Datum absoluto pendiente de confirmación.; Simplificaciones: [{"label":"Transición de la sección","value":"Recogida con ancho inferior 0,40 y superior 0,20 m; pendiente intermedia simplificada","unit":""}]; IncluirEnMediciones: no
JH_AcabadoVisual - Perfil: fence_concrete; Acabado: Basamento de hormigón prefabricado; ColorRGB: [0.72,0.72,0.69]; Rugosidad: 0.88; Metallicidad: 0; Estado: criterio_visual; Referencia: Material indicado en U010. Tono y rugosidad adoptados para visualización.
Name | dimensions | classification | fenceSegmentId = Trazado CAD = Tramo | geometryMetrics | Identificador
Basamento de vallado · Norte | {"documented":[{"label":"Altura sobre terreno","value":0.5,"unit":"m"},{"label":"Profundidad bajo terreno","value":0.5,"unit":"m"},{"label":"Ancho inferior","value":0.4,"unit":"m"},{"label":"Ancho superior","value":0.2,"unit":"m"}],"assumed":[{"label":"Transición de la sección","value":"Recogida con ancho inferior 0,40 y superior 0,20 m; pendiente intermedia simplificada","unit":""}],"geometry":[{"label":"Extensión representada X","value":136.70495,"unit":"m"},{"label":"Extensión representada Y","value":19.234488,"unit":"m"},{"label":"Extensión representada Z","value":3.263874,"unit":"m"}]} | {"layerId":"fences","layerName":"Vallado perimetral","function":"Basamento de vallado · Norte"} | FENCE-21B1A-1 | {"boundingBoxM":{"min":[0.567687,90.320638,0.194078],"max":[137.272637,109.555126,3.457952]},"extentsM":[136.70495,19.234488,3.263874],"meshSurfaceM2":410.683682,"meshVolumeM3":48.96966,"closedSolid":true,"basis":"Modelo de coordinación a partir de planos. Las dimensiones documentadas se separan de las simplificaciones gráficas y cotas de terreno interpoladas; no son cantidades certificadas de obra."} | FENCE-21B1A-1-BASE
Basamento de vallado · Este | {"documented":[{"label":"Altura sobre terreno","value":0.5,"unit":"m"},{"label":"Profundidad bajo terreno","value":0.5,"unit":"m"},{"label":"Ancho inferior","value":0.4,"unit":"m"},{"label":"Ancho superior","value":0.2,"unit":"m"}],"assumed":[{"label":"Transición de la sección","value":"Recogida con ancho inferior 0,40 y superior 0,20 m; pendiente intermedia simplificada","unit":""}],"geometry":[{"label":"Extensión representada X","value":12.506158,"unit":"m"},{"label":"Extensión representada Y","value":87.908897,"unit":"m"},{"label":"Extensión representada Z","value":2.04874,"unit":"m"}]} | {"layerId":"fences","layerName":"Vallado perimetral","function":"Basamento de vallado · Este"} | FENCE-21B1A-2 | {"boundingBoxM":{"min":[124.937293,2.637177,1.409212],"max":[137.443451,90.546074,3.457952]},"extentsM":[12.506158,87.908897,2.04874],"meshSurfaceM2":264.482112,"meshVolumeM3":31.483162,"closedSolid":true,"basis":"Modelo de coordinación a partir de planos. Las dimensiones documentadas se separan de las simplificaciones gráficas y cotas de terreno interpoladas; no son cantidades certificadas de obra."} | FENCE-21B1A-2-BASE
Basamento de vallado · Retorno sureste | {"documented":[{"label":"Altura sobre terreno","value":0.5,"unit":"m"},{"label":"Profundidad bajo terreno","value":0.5,"unit":"m"},{"label":"Ancho inferior","value":0.4,"unit":"m"},{"label":"Ancho superior","value":0.2,"unit":"m"}],"assumed":[{"label":"Transición de la sección","value":"Recogida con ancho inferior 0,40 y superior 0,20 m; pendiente intermedia simplificada","unit":""}],"geometry":[{"label":"Extensión representada X","value":2.035936,"unit":"m"},{"label":"Extensión representada Y","value":0.669749,"unit":"m"},{"label":"Extensión representada Z","value":1.040111,"unit":"m"}]} | {"layerId":"fences","layerName":"Vallado perimetral","function":"Basamento de vallado · Retorno sureste"} | FENCE-21B1A-3 | {"boundingBoxM":{"min":[123.126835,2.466366,1.369101],"max":[125.162771,3.136115,2.409212]},"extentsM":[2.035936,0.669749,1.040111],"meshSurfaceM2":5.954231,"meshVolumeM3":0.710008,"closedSolid":true,"basis":"Modelo de coordinación a partir de planos. Las dimensiones documentadas se separan de las simplificaciones gráficas y cotas de terreno interpoladas; no son cantidades certificadas de obra."} | FENCE-21B1A-3-BASE
Basamento de vallado · Sur | {"documented":[{"label":"Altura sobre terreno","value":0.5,"unit":"m"},{"label":"Profundidad bajo terreno","value":0.5,"unit":"m"},{"label":"Ancho inferior","value":0.4,"unit":"m"},{"label":"Ancho superior","value":0.2,"unit":"m"}],"assumed":[{"label":"Transición de la sección","value":"Recogida con ancho inferior 0,40 y superior 0,20 m; pendiente intermedia simplificada","unit":""}],"geometry":[{"label":"Extensión representada X","value":115.601728,"unit":"m"},{"label":"Extensión representada Y","value":16.347375,"unit":"m"},{"label":"Extensión representada Z","value":2.120162,"unit":"m"}]} | {"layerId":"fences","layerName":"Vallado perimetral","function":"Basamento de vallado · Sur"} | FENCE-21B33-1 | {"boundingBoxM":{"min":[5.994844,2.958706,0.248939],"max":[121.596572,19.306081,2.369101]},"extentsM":[115.601728,16.347375,2.120162],"meshSurfaceM2":347.725658,"meshVolumeM3":41.408198,"closedSolid":true,"basis":"Modelo de coordinación a partir de planos. Las dimensiones documentadas se separan de las simplificaciones gráficas y cotas de terreno interpoladas; no son cantidades certificadas de obra."} | FENCE-21B33-1-BASE
Basamento de vallado · Curva suroeste | {"documented":[{"label":"Altura sobre terreno","value":0.5,"unit":"m"},{"label":"Profundidad bajo terreno","value":0.5,"unit":"m"},{"label":"Ancho inferior","value":0.4,"unit":"m"},{"label":"Ancho superior","value":0.2,"unit":"m"}],"assumed":[{"label":"Transición de la sección","value":"Recogida con ancho inferior 0,40 y superior 0,20 m; pendiente intermedia simplificada","unit":""}],"geometry":[{"label":"Extensión representada X","value":12.371671,"unit":"m"},{"label":"Extensión representada Y","value":18.05911,"unit":"m"},{"label":"Extensión representada Z","value":1.38,"unit":"m"}]} | {"layerId":"fences","layerName":"Vallado perimetral","function":"Basamento de vallado · Curva suroeste"} | FENCE-21B33-2 | {"boundingBoxM":{"min":[-6.308009,18.912307,-0.13],"max":[6.063662,36.971417,1.25]},"extentsM":[12.371671,18.05911,1.38],"meshSurfaceM2":96.509076,"meshVolumeM3":8.448834,"closedSolid":true,"basis":"Modelo de coordinación a partir de planos. Las dimensiones documentadas se separan de las simplificaciones gráficas y cotas de terreno interpoladas; no son cantidades certificadas de obra."} | FENCE-21B33-2-BASE
Basamento de vallado · Oeste | {"documented":[{"label":"Altura sobre terreno","value":0.5,"unit":"m"},{"label":"Profundidad bajo terreno","value":0.5,"unit":"m"},{"label":"Ancho inferior","value":0.4,"unit":"m"},{"label":"Ancho superior","value":0.2,"unit":"m"}],"assumed":[{"label":"Transición de la sección","value":"Recogida con ancho inferior 0,40 y superior 0,20 m; pendiente intermedia simplificada","unit":""}],"geometry":[{"label":"Extensión representada X","value":5.381287,"unit":"m"},{"label":"Extensión representada Y","value":56.519919,"unit":"m"},{"label":"Extensión representada Z","value":1.373946,"unit":"m"}]} | {"layerId":"fences","layerName":"Vallado perimetral","function":"Basamento de vallado · Oeste"} | FENCE-21B33-3 | {"boundingBoxM":{"min":[-5.983232,36.915686,-0.129722],"max":[-0.601945,93.435605,1.244224]},"extentsM":[5.381287,56.519919,1.373946],"meshSurfaceM2":169.268336,"meshVolumeM3":20.129965,"closedSolid":true,"basis":"Modelo de coordinación a partir de planos. Las dimensiones documentadas se separan de las simplificaciones gráficas y cotas de terreno interpoladas; no son cantidades certificadas de obra."} | FENCE-21B33-3-BASE

# IfcWindow (22)
In: Planta baja
Description: Ventana; PredefinedType: WINDOW; Group: Arquitectura; BIM · Arquitectura
JH_DimensionesDelModelo - Espesor utilizado para representación: 0.045 m
Pset_WindowCommon - IsExternal: yes
JH_InformacionBIM - level: Planta baja; category: Ventana; ifcClass: IfcWindow; status: provisional; visualLayer: {"id":"architecture","name":"Arquitectura"}; componentSeparation: {"status":"objeto_independiente","note":"Control de visibilidad del objeto completo; la clasificación no altera la malla."}; classification: {"layerId":"architecture","layerName":"Arquitectura","role":"Ventana","basis":"Clasificación por función del elemento; no modifica las especificaciones documentales."}; layerId: architecture
JH_Trazabilidad - Base geométrica: Anchura y altura del hueco según planos; espesor de carpintería aproximado para visualización.; Sistema de coordenadas: Coordenadas de proyecto en metros; sumar (729400, 4301550, 285) para recuperar las coordenadas UTM y cotas de los planos.; Uso del modelo: Reconstrucción tridimensional de la documentación y revisión preliminar de coordinación; pendiente de revisión por el equipo de diseño.; Espesor de representación (m): 0.045; Representación de la carpintería: Elemento representado por un sólido cerrado único; perfiles de marco y hoja sin detalle de fabricación.; Verificación de la malla: Malla cerrada, orientación coherente de las caras y volumen positivo.; Referencia de implantación: Plano general U004 de 2026-07-31; geometría vectorial del PDF registrada con las coordenadas de lindero indicadas.; Disciplina: Arquitectura; Clase IFC: IfcWindow; Fase del modelo: V0.1 · Reconstrucción documental y coordinación preliminar; Representación geométrica: Sólido de malla triangular cerrada en IFC4; Aplicabilidad de las mediciones: Volumen exclusivamente geométrico; los espesores de representación, las simplificaciones y las envolventes no constituyen mediciones de compra, ejecución, fabricación ni volumen neto de material.; Capa BIM: Arquitectura; Estado del acabado: criterio_visual; Categoria: Ventana; ClaseIFC: IfcWindow; EstadoDeInformacion: provisional; UsoDeLasMagnitudes: Geometría de coordinación. Los volúmenes de referencia y subcomponentes no son cantidades de material ni componentes de fabricación certificados.
JH_EvidenciaDeMaterial - status: known
JH_CapaBIM - IdentificadorCapa: architecture; NombreCapa: Arquitectura; Funcion: Ventana; VisibilidadInicial: yes
JH_AcabadoVisual - Estado: criterio_visual; Nota: La apariencia no certifica el material físico ni el acabado de fabricación.
Name | Document | Material = JH_Trazabilidad, Material = name | Dimensiones de la caja local del elemento (X, Y, Z) | Cota mínima absoluta de la malla (m) | Cota máxima absoluta de la malla (m) | Volumen geométrico bruto (m3) = Volumen geométrico (m³) | Reference = Identificador del elemento = Identificador | ExtensionX (m) | ExtensionY (m) | ExtensionZ (m) = Altura del hueco (m) = Altura del hueco (m) | SuperficieDeLaMalla (m2) | VolumenGeometrico (m3) | buildingId | buildingName = Edificio | material | dimensions | JH_InformacionBIM, source = DocumentoFuente | issues = IncidenciasPendientes | positioning = PosicionYEstado | commonProperties | geometryMetrics | ifcAssociations | materialAppearance | visualizationIdentity | appearance | Planos de referencia | Tipo de carpintería | Anchura del hueco (m) = Anchura del hueco (m) | Altura de antepecho (m) = Altura de antepecho (m) | Comprobación pendiente | Estado de la implantación | Referencia del material = JH_EvidenciaDeMaterial, source | Cota de planta baja terminada (m) | Acabado de visualización = Acabado | Perfil | ColorRGB | Rugosidad | Metallicidad | Referencia | Discrepancia entre versiones
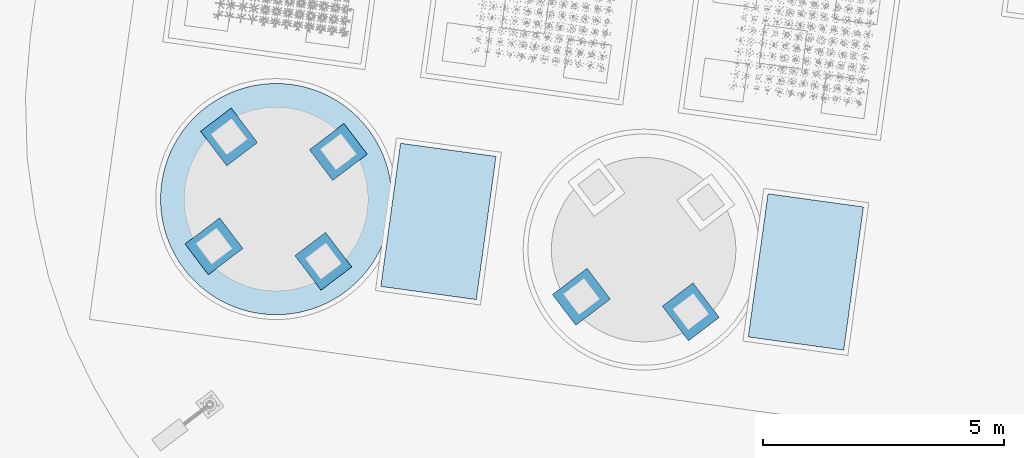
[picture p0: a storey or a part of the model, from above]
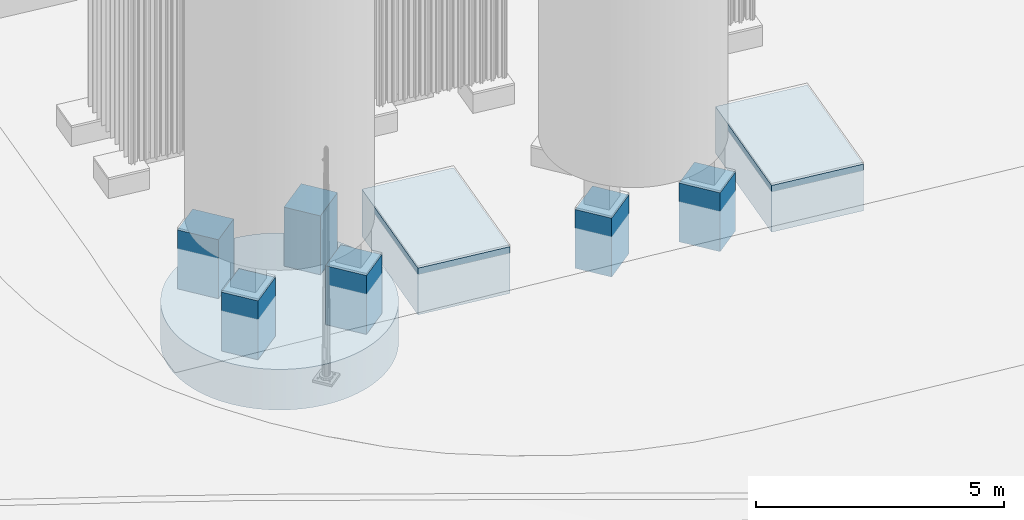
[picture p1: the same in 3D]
Properties of the parts of a building model (IFC4), part 132 of 134

# IfcWindow (22)
Name | Document | Material = JH_Trazabilidad, Material = name | Dimensiones de la caja local del elemento (X, Y, Z) | Cota mínima absoluta de la malla (m) | Cota máxima absoluta de la malla (m) | Volumen geométrico bruto (m3) = Volumen geométrico (m³) | Reference = Identificador del elemento = Identificador | ExtensionX (m) | ExtensionY (m) | ExtensionZ (m) = Altura del hueco (m) = Altura del hueco (m) | SuperficieDeLaMalla (m2) | VolumenGeometrico (m3) | buildingId | buildingName = Edificio | material | dimensions | JH_InformacionBIM, source = DocumentoFuente | issues = IncidenciasPendientes | positioning = PosicionYEstado | commonProperties | geometryMetrics | ifcAssociations | materialAppearance | visualizationIdentity | appearance | Planos de referencia | Tipo de carpintería | Anchura del hueco (m) = Anchura del hueco (m) | Altura de antepecho (m) = Altura de antepecho (m) | Comprobación pendiente | Estado de la implantación | Referencia del material = JH_EvidenciaDeMaterial, source | Cota de planta baja terminada (m) | Acabado de visualización = Acabado | Perfil | ColorRGB | Rugosidad | Metallicidad | Referencia | Discrepancia entre versiones
Sala de bombas contra incendios · ventana C1226_1 | Planos de arquitectura de la sala de bombas contra incendios; Planos de arquitectura de la sala de bombas contra incendios | Aluminio, policarbonato y lamas de ventilación | 1.2 × 0.045 × 2.6 | 287.75 | 290.35 | 0.1404 | pump_house_0042 | 1.19495 | 0.208025 | 2.6 | 6.582 | 0.140398 | pump_house | Sala de bombas contra incendios | {"name":"Aluminio, policarbonato y lamas de ventilación","source":"ARQ-SB-20260710 · A109 / p. 11 y A110 / p. 12","status":"known"} | {"documented":[{"label":"Anchura del hueco","value":1.2,"unit":"m","source":"ARQ-SB-20260710 · Arquitectura A101 / p. 3; Carpinterías A109 / p. 11, A110 / p. 12","status":"documentado"},{"label":"Altura del hueco","value":2.6,"unit":"m","source":"ARQ-SB-20260710 · Arquitectura A101 / p. 3; Carpinterías A109 / p. 11, A110 / p. 12","status":"documentado"},{"label":"Altura de antepecho","value":1.5,"unit":"m","source":"ARQ-SB-20260710 · Arquitectura A101 / p. 3; Carpinterías A109 / p. 11, A110 / p. 12","status":"documentado"}],"geometry":[{"label":"Dimensiones de la caja local del elemento (X, Y, Z)","value":"1.2 × 0.045 × 2.6","unit":"m","source":"Malla triangulada del elemento en ejes locales del edificio","status":"derivado"},{"label":"Cota mínima absoluta de la malla","value":287.75,"unit":"m","source":"Malla de proyecto y origen altimétrico 285 m","status":"derivado"},{"label":"Cota máxima absoluta de la malla","value":290.35,"unit":"m","source":"Malla de proyecto y origen altimétrico 285 m","status":"derivado"},{"label":"Volumen geométrico bruto","value":0.1404,"unit":"m³","source":"Malla cerrada del elemento","status":"derivado"},{"label":"Espesor utilizado para representación","value":0.045,"unit":"m","source":"Hipótesis de visualización, no dimensión de fabricación","status":"provisional"}],"notes":["Las dimensiones documentadas proceden de anotaciones o cuadros; la caja y el volumen se calculan a partir de la malla.","El volumen es exclusivamente geométrico y bruto; no representa una medición neta de material ni una cantidad de compra."]} | {"documentId":"ARQ-SB-20260710","title":"Planos de arquitectura de la sala de bombas contra incendios","date":"2026-07-10","sheet":"Arquitectura A101 / p. 3; Carpinterías A109 / p. 11, A110 / p. 12"} | ["A110 indica antepecho de 1500 mm; otras secciones y alzados sugieren una cota menor. A110 titula la ventana C1290 y el cuadro A109 la identifica como C1226.","Elemento representado por un sólido cerrado único; perfiles de marco y hoja sin detalle de fabricación.","Registro de líneas del PDF general con envolvente de 10,2 × 8,2 m. Estimación de trabajo de implantación de ±0,15 m, pendiente de CAD nativo; no constituye una precisión topográfica garantizada."] | {"horizontalStatus":"derivado","verticalStatus":"provisional","baseElevationM":286.25,"note":"Registro de líneas del PDF general con envolvente de 10,2 × 8,2 m. Estimación de trabajo de implantación de ±0,15 m, pendiente de CAD nativo; no constituye una precisión topográfica garantizada."} | {"Pset_WindowCommon":{"IsExternal":{"value":true,"source":"ARQ-SB-20260710 · A101, A103 y alzados; elemento de la envolvente exterior identificada en planta","status":"known"}}} | {"boundingBoxM":{"min":[10.108009,26.434774,2.75],"max":[11.302955,26.642799,5.35]},"extentsM":[1.194946,0.208025,2.6],"meshSurfaceM2":6.581995,"meshVolumeM3":0.140398,"closedSolid":true,"basis":"Geometría triangulada releída del IFC; envolventes y magnitudes no contractuales."} | {"material":true,"document":true,"quantities":true,"containerGuid":"0Wh59pm9LO_einrwiq6Es1","containerName":"Planta baja"} | {"profileId":"aluminum_polycarbonate","name":"Carpintería de aluminio y policarbonato","materialName":"Aluminio, policarbonato y lamas de ventilación","physicalMaterialStatus":"known","physicalMaterialSource":"ARQ-SB-20260710 · A109 / p. 11 y A110 / p. 12","appearanceStatus":"criterio_visual","appearanceBasis":"Interpretación visual del material documental; el acabado, tono y parámetros PBR no son una especificación contractual.","note":"La apariencia gráfica no modifica ni confirma la especificación física del material."} | {"elementId":"pump_house_0042","ifcGuid":"1S3uNxn3LKKPUoviim1xyv","ifcClass":"IfcWindow","buildingId":"pump_house","buildingName":"Sala de bombas contra incendios","sourceDocumentId":"ARQ-SB-20260710","sourceRepresentationKind":"documentary_mesh"} | {"profileId":"aluminum_polycarbonate","name":"Carpintería de aluminio y policarbonato","status":"criterio_visual","basis":"Interpretación visual del material documental; el acabado, tono y parámetros PBR no son una especificación contractual.","physicalMaterialUnchanged":true} | ARQ-SB-20260710 · Arquitectura A101 / p. 3; Carpinterías A109 / p. 11, A110 / p. 12 | Ventana con lamas de ventilación | 1.2 | 1.5 | A110 indica antepecho de 1500 mm; otras secciones y alzados sugieren una cota menor. A110 titula la ventana C1290 y el cuadro A109 la identifica como C1226. | Registro de líneas del PDF general con envolvente de 10,2 × 8,2 m. Estimación de trabajo de implantación de ±0,15 m, pendiente de CAD nativo; no constituye una precisión topográfica garantizada. | ARQ-SB-20260710 · A109 / p. 11 y A110 / p. 12 | 286.25 | Carpintería de aluminio y policarbonato | aluminum_polycarbonate | [0.721569,0.788235,0.796078] | 0.42 | 0.24 | Interpretación visual del material documental; el acabado, tono y parámetros PBR no son una especificación contractual.
Sala de bombas contra incendios · ventana C1226_2 | Planos de arquitectura de la sala de bombas contra incendios; Planos de arquitectura de la sala de bombas contra incendios | Aluminio, policarbonato y lamas de ventilación | 1.2 × 0.045 × 2.6 | 287.75 | 290.35 | 0.1404 | pump_house_0043 | 1.19495 | 0.208026 | 2.6 | 6.582 | 0.140401 | pump_house | Sala de bombas contra incendios | {"name":"Aluminio, policarbonato y lamas de ventilación","source":"ARQ-SB-20260710 · A109 / p. 11 y A110 / p. 12","status":"known"} | {"documented":[{"label":"Anchura del hueco","value":1.2,"unit":"m","source":"ARQ-SB-20260710 · Arquitectura A101 / p. 3; Carpinterías A109 / p. 11, A110 / p. 12","status":"documentado"},{"label":"Altura del hueco","value":2.6,"unit":"m","source":"ARQ-SB-20260710 · Arquitectura A101 / p. 3; Carpinterías A109 / p. 11, A110 / p. 12","status":"documentado"},{"label":"Altura de antepecho","value":1.5,"unit":"m","source":"ARQ-SB-20260710 · Arquitectura A101 / p. 3; Carpinterías A109 / p. 11, A110 / p. 12","status":"documentado"}],"geometry":[{"label":"Dimensiones de la caja local del elemento (X, Y, Z)","value":"1.2 × 0.045 × 2.6","unit":"m","source":"Malla triangulada del elemento en ejes locales del edificio","status":"derivado"},{"label":"Cota mínima absoluta de la malla","value":287.75,"unit":"m","source":"Malla de proyecto y origen altimétrico 285 m","status":"derivado"},{"label":"Cota máxima absoluta de la malla","value":290.35,"unit":"m","source":"Malla de proyecto y origen altimétrico 285 m","status":"derivado"},{"label":"Volumen geométrico bruto","value":0.1404,"unit":"m³","source":"Malla cerrada del elemento","status":"derivado"},{"label":"Espesor utilizado para representación","value":0.045,"unit":"m","source":"Hipótesis de visualización, no dimensión de fabricación","status":"provisional"}],"notes":["Las dimensiones documentadas proceden de anotaciones o cuadros; la caja y el volumen se calculan a partir de la malla.","El volumen es exclusivamente geométrico y bruto; no representa una medición neta de material ni una cantidad de compra."]} | {"documentId":"ARQ-SB-20260710","title":"Planos de arquitectura de la sala de bombas contra incendios","date":"2026-07-10","sheet":"Arquitectura A101 / p. 3; Carpinterías A109 / p. 11, A110 / p. 12"} | ["Elemento representado por un sólido cerrado único; perfiles de marco y hoja sin detalle de fabricación.","Registro de líneas del PDF general con envolvente de 10,2 × 8,2 m. Estimación de trabajo de implantación de ±0,15 m, pendiente de CAD nativo; no constituye una precisión topográfica garantizada."] | {"horizontalStatus":"derivado","verticalStatus":"provisional","baseElevationM":286.25,"note":"Registro de líneas del PDF general con envolvente de 10,2 × 8,2 m. Estimación de trabajo de implantación de ±0,15 m, pendiente de CAD nativo; no constituye una precisión topográfica garantizada."} | {"Pset_WindowCommon":{"IsExternal":{"value":true,"source":"ARQ-SB-20260710 · A101, A103 y alzados; elemento de la envolvente exterior identificada en planta","status":"known"}}} | {"boundingBoxM":{"min":[15.061413,25.753754,2.75],"max":[16.256359,25.96178,5.35]},"extentsM":[1.194946,0.208026,2.6],"meshSurfaceM2":6.582003,"meshVolumeM3":0.140401,"closedSolid":true,"basis":"Geometría triangulada releída del IFC; envolventes y magnitudes no contractuales."} | {"material":true,"document":true,"quantities":true,"containerGuid":"0Wh59pm9LO_einrwiq6Es1","containerName":"Planta baja"} | {"profileId":"aluminum_polycarbonate","name":"Carpintería de aluminio y policarbonato","materialName":"Aluminio, policarbonato y lamas de ventilación","physicalMaterialStatus":"known","physicalMaterialSource":"ARQ-SB-20260710 · A109 / p. 11 y A110 / p. 12","appearanceStatus":"criterio_visual","appearanceBasis":"Interpretación visual del material documental; el acabado, tono y parámetros PBR no son una especificación contractual.","note":"La apariencia gráfica no modifica ni confirma la especificación física del material."} | {"elementId":"pump_house_0043","ifcGuid":"3YazIso2LKLenQTpPjoj8f","ifcClass":"IfcWindow","buildingId":"pump_house","buildingName":"Sala de bombas contra incendios","sourceDocumentId":"ARQ-SB-20260710","sourceRepresentationKind":"documentary_mesh"} | {"profileId":"aluminum_polycarbonate","name":"Carpintería de aluminio y policarbonato","status":"criterio_visual","basis":"Interpretación visual del material documental; el acabado, tono y parámetros PBR no son una especificación contractual.","physicalMaterialUnchanged":true} | ARQ-SB-20260710 · Arquitectura A101 / p. 3; Carpinterías A109 / p. 11, A110 / p. 12 | Ventana con lamas de ventilación | 1.2 | 1.5 |  | Registro de líneas del PDF general con envolvente de 10,2 × 8,2 m. Estimación de trabajo de implantación de ±0,15 m, pendiente de CAD nativo; no constituye una precisión topográfica garantizada. | ARQ-SB-20260710 · A109 / p. 11 y A110 / p. 12 | 286.25 | Carpintería de aluminio y policarbonato | aluminum_polycarbonate | [0.721569,0.788235,0.796078] | 0.42 | 0.24 | Interpretación visual del material documental; el acabado, tono y parámetros PBR no son una especificación contractual.
Edificio de oficinas · ventana C0923_B_1 | Planos de arquitectura del edificio de oficinas; Planos de arquitectura del edificio de oficinas | Aluminio y acristalamiento 6+12A+6 | 0.9 × 0.045 × 2.3 | 287.05 | 289.35 | 0.09315 | office_0213 | 0.167164 | 0.897742 | 2.3 | 4.428 | 0.0931497 | office | Edificio de oficinas | {"name":"Aluminio y acristalamiento 6+12A+6","source":"ARQ-OF-20260710 · A109 / p. 11","status":"known"} | {"documented":[{"label":"Anchura del hueco","value":0.9,"unit":"m","source":"ARQ-OF-20260710 · Arquitectura A101 / p. 3; Carpinterías A108 / p. 10, A109 / p. 11","status":"documentado"},{"label":"Altura del hueco","value":2.3,"unit":"m","source":"ARQ-OF-20260710 · Arquitectura A101 / p. 3; Carpinterías A108 / p. 10, A109 / p. 11","status":"documentado"},{"label":"Altura de antepecho","value":1.1,"unit":"m","source":"ARQ-OF-20260710 · Arquitectura A101 / p. 3; Carpinterías A108 / p. 10, A109 / p. 11","status":"documentado"}],"geometry":[{"label":"Dimensiones de la caja local del elemento (X, Y, Z)","value":"0.9 × 0.045 × 2.3","unit":"m","source":"Malla triangulada del elemento en ejes locales del edificio","status":"derivado"},{"label":"Cota mínima absoluta de la malla","value":287.05,"unit":"m","source":"Malla de proyecto y origen altimétrico 285 m","status":"derivado"},{"label":"Cota máxima absoluta de la malla","value":289.35,"unit":"m","source":"Malla de proyecto y origen altimétrico 285 m","status":"derivado"},{"label":"Volumen geométrico bruto","value":0.09315,"unit":"m³","source":"Malla cerrada del elemento","status":"derivado"},{"label":"Espesor utilizado para representación","value":0.045,"unit":"m","source":"Hipótesis de visualización, no dimensión de fabricación","status":"provisional"}],"notes":["Las dimensiones documentadas proceden de anotaciones o cuadros; la caja y el volumen se calculan a partir de la malla.","El volumen es exclusivamente geométrico y bruto; no representa una medición neta de material ni una cantidad de compra."]} | {"documentId":"ARQ-OF-20260710","title":"Planos de arquitectura del edificio de oficinas","date":"2026-07-10","sheet":"Arquitectura A101 / p. 3; Carpinterías A108 / p. 10, A109 / p. 11"} | ["Posición deducida de las cadenas de cotas en planta; diferencia de 100 mm al final de la cadena sur pendiente de revisión. Antepecho de +1,100 m según alzado A106.","El plano general de 2026-07-31 mantiene el edificio de oficinas de 200 m², mientras documentación anterior indica su supresión. Se conserva lo dibujado, pendiente de confirmación de la propiedad y del equipo de diseño.","Elemento representado por un sólido cerrado único; perfiles de marco y hoja sin detalle de fabricación.","Registro de líneas del PDF general, envolvente de 20 × 10 m; eje local 1 al norte y acceso del lado A al oeste. Estimación de trabajo de implantación de ±0,15 m, pendiente de CAD; no constituye una precisión topográfica garantizada."] | {"horizontalStatus":"derivado","verticalStatus":"provisional","baseElevationM":285.95,"note":"Registro de líneas del PDF general, envolvente de 20 × 10 m; eje local 1 al norte y acceso del lado A al oeste. Estimación de trabajo de implantación de ±0,15 m, pendiente de CAD; no constituye una precisión topográfica garantizada."} | {"Pset_WindowCommon":{"IsExternal":{"value":true,"source":"ARQ-OF-20260710 · A101, A103 y alzados; elemento de la envolvente exterior identificada en planta","status":"known"}}} | {"boundingBoxM":{"min":[27.110159,89.981255,2.05],"max":[27.277323,90.878997,4.35]},"extentsM":[0.167164,0.897742,2.3],"meshSurfaceM2":4.428,"meshVolumeM3":0.09315,"closedSolid":true,"basis":"Geometría triangulada releída del IFC; envolventes y magnitudes no contractuales."} | {"material":true,"document":true,"quantities":true,"containerGuid":"3ztlotcerHPueDgxP84R6z","containerName":"Planta baja"} | {"profileId":"glass_aluminum","name":"Carpintería acristalada · azul gris","materialName":"Aluminio y acristalamiento 6+12A+6","physicalMaterialStatus":"known","physicalMaterialSource":"ARQ-OF-20260710 · A109 / p. 11","appearanceStatus":"criterio_visual","appearanceBasis":"Composición 6+12A+6 documentada. Transparencia gráfica aplicada al objeto completo; marco y vidrio aún comparten malla.","note":"La apariencia gráfica no modifica ni confirma la especificación física del material."} | {"elementId":"office_0213","ifcGuid":"1NQDrHv0XQr9Iqa0mPiCec","ifcClass":"IfcWindow","buildingId":"office","buildingName":"Edificio de oficinas","sourceDocumentId":"ARQ-OF-20260710","sourceRepresentationKind":"documentary_mesh"} | {"profileId":"glass_aluminum","name":"Carpintería acristalada · azul gris","status":"criterio_visual","basis":"Composición 6+12A+6 documentada. Transparencia gráfica aplicada al objeto completo; marco y vidrio aún comparten malla.","physicalMaterialUnchanged":true} | ARQ-OF-20260710 · Arquitectura A101 / p. 3; Carpinterías A108 / p. 10, A109 / p. 11 | Ventana | 0.9 | 1.1 | Posición deducida de las cadenas de cotas en planta; diferencia de 100 mm al final de la cadena sur pendiente de revisión. Antepecho de +1,100 m según alzado A106. | Registro de líneas del PDF general, envolvente de 20 × 10 m; eje local 1 al norte y acceso del lado A al oeste. Estimación de trabajo de implantación de ±0,15 m, pendiente de CAD; no constituye una precisión topográfica garantizada. | ARQ-OF-20260710 · A109 / p. 11 | 285.95 | Carpintería acristalada · azul gris | glass_aluminum | [0.560784,0.682353,0.721569] | 0.2 | 0.1 | Composición 6+12A+6 documentada. Transparencia gráfica aplicada al objeto completo; marco y vidrio aún comparten malla. | El plano general de 2026-07-31 mantiene el edificio de oficinas de 200 m², mientras documentación anterior indica su supresión. Se conserva lo dibujado, pendiente de confirmación de la propiedad y del equipo de diseño.
Edificio de oficinas · ventana C0923_B_2 | Planos de arquitectura del edificio de oficinas; Planos de arquitectura del edificio de oficinas | Aluminio y acristalamiento 6+12A+6 | 0.9 × 0.045 × 2.3 | 287.05 | 289.35 | 0.09315 | office_0214 | 0.167164 | 0.897742 | 2.3 | 4.428 | 0.0931498 | office | Edificio de oficinas | {"name":"Aluminio y acristalamiento 6+12A+6","source":"ARQ-OF-20260710 · A109 / p. 11","status":"known"} | {"documented":[{"label":"Anchura del hueco","value":0.9,"unit":"m","source":"ARQ-OF-20260710 · Arquitectura A101 / p. 3; Carpinterías A108 / p. 10, A109 / p. 11","status":"documentado"},{"label":"Altura del hueco","value":2.3,"unit":"m","source":"ARQ-OF-20260710 · Arquitectura A101 / p. 3; Carpinterías A108 / p. 10, A109 / p. 11","status":"documentado"},{"label":"Altura de antepecho","value":1.1,"unit":"m","source":"ARQ-OF-20260710 · Arquitectura A101 / p. 3; Carpinterías A108 / p. 10, A109 / p. 11","status":"documentado"}],"geometry":[{"label":"Dimensiones de la caja local del elemento (X, Y, Z)","value":"0.9 × 0.045 × 2.3","unit":"m","source":"Malla triangulada del elemento en ejes locales del edificio","status":"derivado"},{"label":"Cota mínima absoluta de la malla","value":287.05,"unit":"m","source":"Malla de proyecto y origen altimétrico 285 m","status":"derivado"},{"label":"Cota máxima absoluta de la malla","value":289.35,"unit":"m","source":"Malla de proyecto y origen altimétrico 285 m","status":"derivado"},{"label":"Volumen geométrico bruto","value":0.09315,"unit":"m³","source":"Malla cerrada del elemento","status":"derivado"},{"label":"Espesor utilizado para representación","value":0.045,"unit":"m","source":"Hipótesis de visualización, no dimensión de fabricación","status":"provisional"}],"notes":["Las dimensiones documentadas proceden de anotaciones o cuadros; la caja y el volumen se calculan a partir de la malla.","El volumen es exclusivamente geométrico y bruto; no representa una medición neta de material ni una cantidad de compra."]} | {"documentId":"ARQ-OF-20260710","title":"Planos de arquitectura del edificio de oficinas","date":"2026-07-10","sheet":"Arquitectura A101 / p. 3; Carpinterías A108 / p. 10, A109 / p. 11"} | ["Posición deducida de las cadenas de cotas en planta; diferencia de 100 mm al final de la cadena sur pendiente de revisión. Antepecho de +1,100 m según alzado A106.","El plano general de 2026-07-31 mantiene el edificio de oficinas de 200 m², mientras documentación anterior indica su supresión. Se conserva lo dibujado, pendiente de confirmación de la propiedad y del equipo de diseño.","Elemento representado por un sólido cerrado único; perfiles de marco y hoja sin detalle de fabricación.","Registro de líneas del PDF general, envolvente de 20 × 10 m; eje local 1 al norte y acceso del lado A al oeste. Estimación de trabajo de implantación de ±0,15 m, pendiente de CAD; no constituye una precisión topográfica garantizada."] | {"horizontalStatus":"derivado","verticalStatus":"provisional","baseElevationM":285.95,"note":"Registro de líneas del PDF general, envolvente de 20 × 10 m; eje local 1 al norte y acceso del lado A al oeste. Estimación de trabajo de implantación de ±0,15 m, pendiente de CAD; no constituye una precisión topográfica garantizada."} | {"Pset_WindowCommon":{"IsExternal":{"value":true,"source":"ARQ-OF-20260710 · A101, A103 y alzados; elemento de la envolvente exterior identificada en planta","status":"known"}}} | {"boundingBoxM":{"min":[26.864992,88.19803,2.05],"max":[27.032156,89.095772,4.35]},"extentsM":[0.167164,0.897742,2.3],"meshSurfaceM2":4.427998,"meshVolumeM3":0.09315,"closedSolid":true,"basis":"Geometría triangulada releída del IFC; envolventes y magnitudes no contractuales."} | {"material":true,"document":true,"quantities":true,"containerGuid":"3ztlotcerHPueDgxP84R6z","containerName":"Planta baja"} | {"profileId":"glass_aluminum","name":"Carpintería acristalada · azul gris","materialName":"Aluminio y acristalamiento 6+12A+6","physicalMaterialStatus":"known","physicalMaterialSource":"ARQ-OF-20260710 · A109 / p. 11","appearanceStatus":"criterio_visual","appearanceBasis":"Composición 6+12A+6 documentada. Transparencia gráfica aplicada al objeto completo; marco y vidrio aún comparten malla.","note":"La apariencia gráfica no modifica ni confirma la especificación física del material."} | {"elementId":"office_0214","ifcGuid":"1FObYchJHTu9WWYkjbC3hj","ifcClass":"IfcWindow","buildingId":"office","buildingName":"Edificio de oficinas","sourceDocumentId":"ARQ-OF-20260710","sourceRepresentationKind":"documentary_mesh"} | {"profileId":"glass_aluminum","name":"Carpintería acristalada · azul gris","status":"criterio_visual","basis":"Composición 6+12A+6 documentada. Transparencia gráfica aplicada al objeto completo; marco y vidrio aún comparten malla.","physicalMaterialUnchanged":true} | ARQ-OF-20260710 · Arquitectura A101 / p. 3; Carpinterías A108 / p. 10, A109 / p. 11 | Ventana | 0.9 | 1.1 | Posición deducida de las cadenas de cotas en planta; diferencia de 100 mm al final de la cadena sur pendiente de revisión. Antepecho de +1,100 m según alzado A106. | Registro de líneas del PDF general, envolvente de 20 × 10 m; eje local 1 al norte y acceso del lado A al oeste. Estimación de trabajo de implantación de ±0,15 m, pendiente de CAD; no constituye una precisión topográfica garantizada. | ARQ-OF-20260710 · A109 / p. 11 | 285.95 | Carpintería acristalada · azul gris | glass_aluminum | [0.560784,0.682353,0.721569] | 0.2 | 0.1 | Composición 6+12A+6 documentada. Transparencia gráfica aplicada al objeto completo; marco y vidrio aún comparten malla. | El plano general de 2026-07-31 mantiene el edificio de oficinas de 200 m², mientras documentación anterior indica su supresión. Se conserva lo dibujado, pendiente de confirmación de la propiedad y del equipo de diseño.
Edificio de oficinas · ventana C0923_B_3 | Planos de arquitectura del edificio de oficinas; Planos de arquitectura del edificio de oficinas | Aluminio y acristalamiento 6+12A+6 | 0.9 × 0.045 × 2.3 | 287.05 | 289.35 | 0.09315 | office_0215 | 0.167164 | 0.897742 | 2.3 | 4.428 | 0.0931497 | office | Edificio de oficinas | {"name":"Aluminio y acristalamiento 6+12A+6","source":"ARQ-OF-20260710 · A109 / p. 11","status":"known"} | {"documented":[{"label":"Anchura del hueco","value":0.9,"unit":"m","source":"ARQ-OF-20260710 · Arquitectura A101 / p. 3; Carpinterías A108 / p. 10, A109 / p. 11","status":"documentado"},{"label":"Altura del hueco","value":2.3,"unit":"m","source":"ARQ-OF-20260710 · Arquitectura A101 / p. 3; Carpinterías A108 / p. 10, A109 / p. 11","status":"documentado"},{"label":"Altura de antepecho","value":1.1,"unit":"m","source":"ARQ-OF-20260710 · Arquitectura A101 / p. 3; Carpinterías A108 / p. 10, A109 / p. 11","status":"documentado"}],"geometry":[{"label":"Dimensiones de la caja local del elemento (X, Y, Z)","value":"0.9 × 0.045 × 2.3","unit":"m","source":"Malla triangulada del elemento en ejes locales del edificio","status":"derivado"},{"label":"Cota mínima absoluta de la malla","value":287.05,"unit":"m","source":"Malla de proyecto y origen altimétrico 285 m","status":"derivado"},{"label":"Cota máxima absoluta de la malla","value":289.35,"unit":"m","source":"Malla de proyecto y origen altimétrico 285 m","status":"derivado"},{"label":"Volumen geométrico bruto","value":0.09315,"unit":"m³","source":"Malla cerrada del elemento","status":"derivado"},{"label":"Espesor utilizado para representación","value":0.045,"unit":"m","source":"Hipótesis de visualización, no dimensión de fabricación","status":"provisional"}],"notes":["Las dimensiones documentadas proceden de anotaciones o cuadros; la caja y el volumen se calculan a partir de la malla.","El volumen es exclusivamente geométrico y bruto; no representa una medición neta de material ni una cantidad de compra."]} | {"documentId":"ARQ-OF-20260710","title":"Planos de arquitectura del edificio de oficinas","date":"2026-07-10","sheet":"Arquitectura A101 / p. 3; Carpinterías A108 / p. 10, A109 / p. 11"} | ["Posición deducida de las cadenas de cotas en planta; diferencia de 100 mm al final de la cadena sur pendiente de revisión. Antepecho de +1,100 m según alzado A106.","El plano general de 2026-07-31 mantiene el edificio de oficinas de 200 m², mientras documentación anterior indica su supresión. Se conserva lo dibujado, pendiente de confirmación de la propiedad y del equipo de diseño.","Elemento representado por un sólido cerrado único; perfiles de marco y hoja sin detalle de fabricación.","Registro de líneas del PDF general, envolvente de 20 × 10 m; eje local 1 al norte y acceso del lado A al oeste. Estimación de trabajo de implantación de ±0,15 m, pendiente de CAD; no constituye una precisión topográfica garantizada."] | {"horizontalStatus":"derivado","verticalStatus":"provisional","baseElevationM":285.95,"note":"Registro de líneas del PDF general, envolvente de 20 × 10 m; eje local 1 al norte y acceso del lado A al oeste. Estimación de trabajo de implantación de ±0,15 m, pendiente de CAD; no constituye una precisión topográfica garantizada."} | {"Pset_WindowCommon":{"IsExternal":{"value":true,"source":"ARQ-OF-20260710 · A101, A103 y alzados; elemento de la envolvente exterior identificada en planta","status":"known"}}} | {"boundingBoxM":{"min":[26.619825,86.414804,2.05],"max":[26.786989,87.312546,4.35]},"extentsM":[0.167164,0.897742,2.3],"meshSurfaceM2":4.428,"meshVolumeM3":0.09315,"closedSolid":true,"basis":"Geometría triangulada releída del IFC; envolventes y magnitudes no contractuales."} | {"material":true,"document":true,"quantities":true,"containerGuid":"3ztlotcerHPueDgxP84R6z","containerName":"Planta baja"} | {"profileId":"glass_aluminum","name":"Carpintería acristalada · azul gris","materialName":"Aluminio y acristalamiento 6+12A+6","physicalMaterialStatus":"known","physicalMaterialSource":"ARQ-OF-20260710 · A109 / p. 11","appearanceStatus":"criterio_visual","appearanceBasis":"Composición 6+12A+6 documentada. Transparencia gráfica aplicada al objeto completo; marco y vidrio aún comparten malla.","note":"La apariencia gráfica no modifica ni confirma la especificación física del material."} | {"elementId":"office_0215","ifcGuid":"3j_e7Y7YnPLhDIsyd5PdPh","ifcClass":"IfcWindow","buildingId":"office","buildingName":"Edificio de oficinas","sourceDocumentId":"ARQ-OF-20260710","sourceRepresentationKind":"documentary_mesh"} | {"profileId":"glass_aluminum","name":"Carpintería acristalada · azul gris","status":"criterio_visual","basis":"Composición 6+12A+6 documentada. Transparencia gráfica aplicada al objeto completo; marco y vidrio aún comparten malla.","physicalMaterialUnchanged":true} | ARQ-OF-20260710 · Arquitectura A101 / p. 3; Carpinterías A108 / p. 10, A109 / p. 11 | Ventana | 0.9 | 1.1 | Posición deducida de las cadenas de cotas en planta; diferencia de 100 mm al final de la cadena sur pendiente de revisión. Antepecho de +1,100 m según alzado A106. | Registro de líneas del PDF general, envolvente de 20 × 10 m; eje local 1 al norte y acceso del lado A al oeste. Estimación de trabajo de implantación de ±0,15 m, pendiente de CAD; no constituye una precisión topográfica garantizada. | ARQ-OF-20260710 · A109 / p. 11 | 285.95 | Carpintería acristalada · azul gris | glass_aluminum | [0.560784,0.682353,0.721569] | 0.2 | 0.1 | Composición 6+12A+6 documentada. Transparencia gráfica aplicada al objeto completo; marco y vidrio aún comparten malla. | El plano general de 2026-07-31 mantiene el edificio de oficinas de 200 m², mientras documentación anterior indica su supresión. Se conserva lo dibujado, pendiente de confirmación de la propiedad y del equipo de diseño.
Edificio de oficinas · ventana C0923_B_4 | Planos de arquitectura del edificio de oficinas; Planos de arquitectura del edificio de oficinas | Aluminio y acristalamiento 6+12A+6 | 0.9 × 0.045 × 2.3 | 287.05 | 289.35 | 0.09315 | office_0216 | 0.167165 | 0.897742 | 2.3 | 4.428 | 0.0931508 | office | Edificio de oficinas | {"name":"Aluminio y acristalamiento 6+12A+6","source":"ARQ-OF-20260710 · A109 / p. 11","status":"known"} | {"documented":[{"label":"Anchura del hueco","value":0.9,"unit":"m","source":"ARQ-OF-20260710 · Arquitectura A101 / p. 3; Carpinterías A108 / p. 10, A109 / p. 11","status":"documentado"},{"label":"Altura del hueco","value":2.3,"unit":"m","source":"ARQ-OF-20260710 · Arquitectura A101 / p. 3; Carpinterías A108 / p. 10, A109 / p. 11","status":"documentado"},{"label":"Altura de antepecho","value":1.1,"unit":"m","source":"ARQ-OF-20260710 · Arquitectura A101 / p. 3; Carpinterías A108 / p. 10, A109 / p. 11","status":"documentado"}],"geometry":[{"label":"Dimensiones de la caja local del elemento (X, Y, Z)","value":"0.9 × 0.045 × 2.3","unit":"m","source":"Malla triangulada del elemento en ejes locales del edificio","status":"derivado"},{"label":"Cota mínima absoluta de la malla","value":287.05,"unit":"m","source":"Malla de proyecto y origen altimétrico 285 m","status":"derivado"},{"label":"Cota máxima absoluta de la malla","value":289.35,"unit":"m","source":"Malla de proyecto y origen altimétrico 285 m","status":"derivado"},{"label":"Volumen geométrico bruto","value":0.09315,"unit":"m³","source":"Malla cerrada del elemento","status":"derivado"},{"label":"Espesor utilizado para representación","value":0.045,"unit":"m","source":"Hipótesis de visualización, no dimensión de fabricación","status":"provisional"}],"notes":["Las dimensiones documentadas proceden de anotaciones o cuadros; la caja y el volumen se calculan a partir de la malla.","El volumen es exclusivamente geométrico y bruto; no representa una medición neta de material ni una cantidad de compra."]} | {"documentId":"ARQ-OF-20260710","title":"Planos de arquitectura del edificio de oficinas","date":"2026-07-10","sheet":"Arquitectura A101 / p. 3; Carpinterías A108 / p. 10, A109 / p. 11"} | ["Posición deducida de las cadenas de cotas en planta; diferencia de 100 mm al final de la cadena sur pendiente de revisión. Antepecho de +1,100 m según alzado A106.","El plano general de 2026-07-31 mantiene el edificio de oficinas de 200 m², mientras documentación anterior indica su supresión. Se conserva lo dibujado, pendiente de confirmación de la propiedad y del equipo de diseño.","Elemento representado por un sólido cerrado único; perfiles de marco y hoja sin detalle de fabricación.","Registro de líneas del PDF general, envolvente de 20 × 10 m; eje local 1 al norte y acceso del lado A al oeste. Estimación de trabajo de implantación de ±0,15 m, pendiente de CAD; no constituye una precisión topográfica garantizada."] | {"horizontalStatus":"derivado","verticalStatus":"provisional","baseElevationM":285.95,"note":"Registro de líneas del PDF general, envolvente de 20 × 10 m; eje local 1 al norte y acceso del lado A al oeste. Estimación de trabajo de implantación de ±0,15 m, pendiente de CAD; no constituye una precisión topográfica garantizada."} | {"Pset_WindowCommon":{"IsExternal":{"value":true,"source":"ARQ-OF-20260710 · A101, A103 y alzados; elemento de la envolvente exterior identificada en planta","status":"known"}}} | {"boundingBoxM":{"min":[26.374657,84.631579,2.05],"max":[26.541822,85.529321,4.35]},"extentsM":[0.167165,0.897742,2.3],"meshSurfaceM2":4.428002,"meshVolumeM3":0.093151,"closedSolid":true,"basis":"Geometría triangulada releída del IFC; envolventes y magnitudes no contractuales."} | {"material":true,"document":true,"quantities":true,"containerGuid":"3ztlotcerHPueDgxP84R6z","containerName":"Planta baja"} | {"profileId":"glass_aluminum","name":"Carpintería acristalada · azul gris","materialName":"Aluminio y acristalamiento 6+12A+6","physicalMaterialStatus":"known","physicalMaterialSource":"ARQ-OF-20260710 · A109 / p. 11","appearanceStatus":"criterio_visual","appearanceBasis":"Composición 6+12A+6 documentada. Transparencia gráfica aplicada al objeto completo; marco y vidrio aún comparten malla.","note":"La apariencia gráfica no modifica ni confirma la especificación física del material."} | {"elementId":"office_0216","ifcGuid":"0ns8TWNrfUbADmiSsM9y5A","ifcClass":"IfcWindow","buildingId":"office","buildingName":"Edificio de oficinas","sourceDocumentId":"ARQ-OF-20260710","sourceRepresentationKind":"documentary_mesh"} | {"profileId":"glass_aluminum","name":"Carpintería acristalada · azul gris","status":"criterio_visual","basis":"Composición 6+12A+6 documentada. Transparencia gráfica aplicada al objeto completo; marco y vidrio aún comparten malla.","physicalMaterialUnchanged":true} | ARQ-OF-20260710 · Arquitectura A101 / p. 3; Carpinterías A108 / p. 10, A109 / p. 11 | Ventana | 0.9 | 1.1 | Posición deducida de las cadenas de cotas en planta; diferencia de 100 mm al final de la cadena sur pendiente de revisión. Antepecho de +1,100 m según alzado A106. | Registro de líneas del PDF general, envolvente de 20 × 10 m; eje local 1 al norte y acceso del lado A al oeste. Estimación de trabajo de implantación de ±0,15 m, pendiente de CAD; no constituye una precisión topográfica garantizada. | ARQ-OF-20260710 · A109 / p. 11 | 285.95 | Carpintería acristalada · azul gris | glass_aluminum | [0.560784,0.682353,0.721569] | 0.2 | 0.1 | Composición 6+12A+6 documentada. Transparencia gráfica aplicada al objeto completo; marco y vidrio aún comparten malla. | El plano general de 2026-07-31 mantiene el edificio de oficinas de 200 m², mientras documentación anterior indica su supresión. Se conserva lo dibujado, pendiente de confirmación de la propiedad y del equipo de diseño.
Edificio de oficinas · ventana C0923_B_5 | Planos de arquitectura del edificio de oficinas; Planos de arquitectura del edificio de oficinas | Aluminio y acristalamiento 6+12A+6 | 0.9 × 0.045 × 2.3 | 287.05 | 289.35 | 0.09315 | office_0217 | 0.167165 | 0.897742 | 2.3 | 4.428 | 0.0931507 | office | Edificio de oficinas | {"name":"Aluminio y acristalamiento 6+12A+6","source":"ARQ-OF-20260710 · A109 / p. 11","status":"known"} | {"documented":[{"label":"Anchura del hueco","value":0.9,"unit":"m","source":"ARQ-OF-20260710 · Arquitectura A101 / p. 3; Carpinterías A108 / p. 10, A109 / p. 11","status":"documentado"},{"label":"Altura del hueco","value":2.3,"unit":"m","source":"ARQ-OF-20260710 · Arquitectura A101 / p. 3; Carpinterías A108 / p. 10, A109 / p. 11","status":"documentado"},{"label":"Altura de antepecho","value":1.1,"unit":"m","source":"ARQ-OF-20260710 · Arquitectura A101 / p. 3; Carpinterías A108 / p. 10, A109 / p. 11","status":"documentado"}],"geometry":[{"label":"Dimensiones de la caja local del elemento (X, Y, Z)","value":"0.9 × 0.045 × 2.3","unit":"m","source":"Malla triangulada del elemento en ejes locales del edificio","status":"derivado"},{"label":"Cota mínima absoluta de la malla","value":287.05,"unit":"m","source":"Malla de proyecto y origen altimétrico 285 m","status":"derivado"},{"label":"Cota máxima absoluta de la malla","value":289.35,"unit":"m","source":"Malla de proyecto y origen altimétrico 285 m","status":"derivado"},{"label":"Volumen geométrico bruto","value":0.09315,"unit":"m³","source":"Malla cerrada del elemento","status":"derivado"},{"label":"Espesor utilizado para representación","value":0.045,"unit":"m","source":"Hipótesis de visualización, no dimensión de fabricación","status":"provisional"}],"notes":["Las dimensiones documentadas proceden de anotaciones o cuadros; la caja y el volumen se calculan a partir de la malla.","El volumen es exclusivamente geométrico y bruto; no representa una medición neta de material ni una cantidad de compra."]} | {"documentId":"ARQ-OF-20260710","title":"Planos de arquitectura del edificio de oficinas","date":"2026-07-10","sheet":"Arquitectura A101 / p. 3; Carpinterías A108 / p. 10, A109 / p. 11"} | ["Posición deducida de las cadenas de cotas en planta; diferencia de 100 mm al final de la cadena sur pendiente de revisión. Antepecho de +1,100 m según alzado A106.","El plano general de 2026-07-31 mantiene el edificio de oficinas de 200 m², mientras documentación anterior indica su supresión. Se conserva lo dibujado, pendiente de confirmación de la propiedad y del equipo de diseño.","Elemento representado por un sólido cerrado único; perfiles de marco y hoja sin detalle de fabricación.","Registro de líneas del PDF general, envolvente de 20 × 10 m; eje local 1 al norte y acceso del lado A al oeste. Estimación de trabajo de implantación de ±0,15 m, pendiente de CAD; no constituye una precisión topográfica garantizada."] | {"horizontalStatus":"derivado","verticalStatus":"provisional","baseElevationM":285.95,"note":"Registro de líneas del PDF general, envolvente de 20 × 10 m; eje local 1 al norte y acceso del lado A al oeste. Estimación de trabajo de implantación de ±0,15 m, pendiente de CAD; no constituye una precisión topográfica garantizada."} | {"Pset_WindowCommon":{"IsExternal":{"value":true,"source":"ARQ-OF-20260710 · A101, A103 y alzados; elemento de la envolvente exterior identificada en planta","status":"known"}}} | {"boundingBoxM":{"min":[26.12949,82.848353,2.05],"max":[26.296655,83.746095,4.35]},"extentsM":[0.167165,0.897742,2.3],"meshSurfaceM2":4.428004,"meshVolumeM3":0.093151,"closedSolid":true,"basis":"Geometría triangulada releída del IFC; envolventes y magnitudes no contractuales."} | {"material":true,"document":true,"quantities":true,"containerGuid":"3ztlotcerHPueDgxP84R6z","containerName":"Planta baja"} | {"profileId":"glass_aluminum","name":"Carpintería acristalada · azul gris","materialName":"Aluminio y acristalamiento 6+12A+6","physicalMaterialStatus":"known","physicalMaterialSource":"ARQ-OF-20260710 · A109 / p. 11","appearanceStatus":"criterio_visual","appearanceBasis":"Composición 6+12A+6 documentada. Transparencia gráfica aplicada al objeto completo; marco y vidrio aún comparten malla.","note":"La apariencia gráfica no modifica ni confirma la especificación física del material."} | {"elementId":"office_0217","ifcGuid":"0wX7y5fzzO4fUXUuznbevQ","ifcClass":"IfcWindow","buildingId":"office","buildingName":"Edificio de oficinas","sourceDocumentId":"ARQ-OF-20260710","sourceRepresentationKind":"documentary_mesh"} | {"profileId":"glass_aluminum","name":"Carpintería acristalada · azul gris","status":"criterio_visual","basis":"Composición 6+12A+6 documentada. Transparencia gráfica aplicada al objeto completo; marco y vidrio aún comparten malla.","physicalMaterialUnchanged":true} | ARQ-OF-20260710 · Arquitectura A101 / p. 3; Carpinterías A108 / p. 10, A109 / p. 11 | Ventana | 0.9 | 1.1 | Posición deducida de las cadenas de cotas en planta; diferencia de 100 mm al final de la cadena sur pendiente de revisión. Antepecho de +1,100 m según alzado A106. | Registro de líneas del PDF general, envolvente de 20 × 10 m; eje local 1 al norte y acceso del lado A al oeste. Estimación de trabajo de implantación de ±0,15 m, pendiente de CAD; no constituye una precisión topográfica garantizada. | ARQ-OF-20260710 · A109 / p. 11 | 285.95 | Carpintería acristalada · azul gris | glass_aluminum | [0.560784,0.682353,0.721569] | 0.2 | 0.1 | Composición 6+12A+6 documentada. Transparencia gráfica aplicada al objeto completo; marco y vidrio aún comparten malla. | El plano general de 2026-07-31 mantiene el edificio de oficinas de 200 m², mientras documentación anterior indica su supresión. Se conserva lo dibujado, pendiente de confirmación de la propiedad y del equipo de diseño.
Edificio de oficinas · ventana C0623_B_1 | Planos de arquitectura del edificio de oficinas; Planos de arquitectura del edificio de oficinas | Aluminio y acristalamiento 6+12A+6 | 0.6 × 0.045 × 2.3 | 287.05 | 289.35 | 0.0621 | office_0218 | 0.126303 | 0.600537 | 2.3 | 3.021 | 0.0620997 | office | Edificio de oficinas | {"name":"Aluminio y acristalamiento 6+12A+6","source":"ARQ-OF-20260710 · A109 / p. 11","status":"known"} | {"documented":[{"label":"Anchura del hueco","value":0.6,"unit":"m","source":"ARQ-OF-20260710 · Arquitectura A101 / p. 3; Carpinterías A108 / p. 10, A109 / p. 11","status":"documentado"},{"label":"Altura del hueco","value":2.3,"unit":"m","source":"ARQ-OF-20260710 · Arquitectura A101 / p. 3; Carpinterías A108 / p. 10, A109 / p. 11","status":"documentado"},{"label":"Altura de antepecho","value":1.1,"unit":"m","source":"ARQ-OF-20260710 · Arquitectura A101 / p. 3; Carpinterías A108 / p. 10, A109 / p. 11","status":"documentado"}],"geometry":[{"label":"Dimensiones de la caja local del elemento (X, Y, Z)","value":"0.6 × 0.045 × 2.3","unit":"m","source":"Malla triangulada del elemento en ejes locales del edificio","status":"derivado"},{"label":"Cota mínima absoluta de la malla","value":287.05,"unit":"m","source":"Malla de proyecto y origen altimétrico 285 m","status":"derivado"},{"label":"Cota máxima absoluta de la malla","value":289.35,"unit":"m","source":"Malla de proyecto y origen altimétrico 285 m","status":"derivado"},{"label":"Volumen geométrico bruto","value":0.0621,"unit":"m³","source":"Malla cerrada del elemento","status":"derivado"},{"label":"Espesor utilizado para representación","value":0.045,"unit":"m","source":"Hipótesis de visualización, no dimensión de fabricación","status":"provisional"}],"notes":["Las dimensiones documentadas proceden de anotaciones o cuadros; la caja y el volumen se calculan a partir de la malla.","El volumen es exclusivamente geométrico y bruto; no representa una medición neta de material ni una cantidad de compra."]} | {"documentId":"ARQ-OF-20260710","title":"Planos de arquitectura del edificio de oficinas","date":"2026-07-10","sheet":"Arquitectura A101 / p. 3; Carpinterías A108 / p. 10, A109 / p. 11"} | ["Posición deducida de las cadenas de cotas en planta; diferencia de 100 mm al final de la cadena sur pendiente de revisión. Antepecho de +1,100 m según alzado A106.","El plano general de 2026-07-31 mantiene el edificio de oficinas de 200 m², mientras documentación anterior indica su supresión. Se conserva lo dibujado, pendiente de confirmación de la propiedad y del equipo de diseño.","Elemento representado por un sólido cerrado único; perfiles de marco y hoja sin detalle de fabricación.","Registro de líneas del PDF general, envolvente de 20 × 10 m; eje local 1 al norte y acceso del lado A al oeste. Estimación de trabajo de implantación de ±0,15 m, pendiente de CAD; no constituye una precisión topográfica garantizada."] | {"horizontalStatus":"derivado","verticalStatus":"provisional","baseElevationM":285.95,"note":"Registro de líneas del PDF general, envolvente de 20 × 10 m; eje local 1 al norte y acceso del lado A al oeste. Estimación de trabajo de implantación de ±0,15 m, pendiente de CAD; no constituye una precisión topográfica garantizada."} | {"Pset_WindowCommon":{"IsExternal":{"value":true,"source":"ARQ-OF-20260710 · A101, A103 y alzados; elemento de la envolvente exterior identificada en planta","status":"known"}}} | {"boundingBoxM":{"min":[25.393989,77.498677,2.05],"max":[25.520292,78.099214,4.35]},"extentsM":[0.126303,0.600537,2.3],"meshSurfaceM2":3.020997,"meshVolumeM3":0.0621,"closedSolid":true,"basis":"Geometría triangulada releída del IFC; envolventes y magnitudes no contractuales."} | {"material":true,"document":true,"quantities":true,"containerGuid":"3ztlotcerHPueDgxP84R6z","containerName":"Planta baja"} | {"profileId":"glass_aluminum","name":"Carpintería acristalada · azul gris","materialName":"Aluminio y acristalamiento 6+12A+6","physicalMaterialStatus":"known","physicalMaterialSource":"ARQ-OF-20260710 · A109 / p. 11","appearanceStatus":"criterio_visual","appearanceBasis":"Composición 6+12A+6 documentada. Transparencia gráfica aplicada al objeto completo; marco y vidrio aún comparten malla.","note":"La apariencia gráfica no modifica ni confirma la especificación física del material."} | {"elementId":"office_0218","ifcGuid":"12NkVoRxbHjwwcfyr6xF22","ifcClass":"IfcWindow","buildingId":"office","buildingName":"Edificio de oficinas","sourceDocumentId":"ARQ-OF-20260710","sourceRepresentationKind":"documentary_mesh"} | {"profileId":"glass_aluminum","name":"Carpintería acristalada · azul gris","status":"criterio_visual","basis":"Composición 6+12A+6 documentada. Transparencia gráfica aplicada al objeto completo; marco y vidrio aún comparten malla.","physicalMaterialUnchanged":true} | ARQ-OF-20260710 · Arquitectura A101 / p. 3; Carpinterías A108 / p. 10, A109 / p. 11 | Ventana | 0.6 | 1.1 | Posición deducida de las cadenas de cotas en planta; diferencia de 100 mm al final de la cadena sur pendiente de revisión. Antepecho de +1,100 m según alzado A106. | Registro de líneas del PDF general, envolvente de 20 × 10 m; eje local 1 al norte y acceso del lado A al oeste. Estimación de trabajo de implantación de ±0,15 m, pendiente de CAD; no constituye una precisión topográfica garantizada. | ARQ-OF-20260710 · A109 / p. 11 | 285.95 | Carpintería acristalada · azul gris | glass_aluminum | [0.560784,0.682353,0.721569] | 0.2 | 0.1 | Composición 6+12A+6 documentada. Transparencia gráfica aplicada al objeto completo; marco y vidrio aún comparten malla. | El plano general de 2026-07-31 mantiene el edificio de oficinas de 200 m², mientras documentación anterior indica su supresión. Se conserva lo dibujado, pendiente de confirmación de la propiedad y del equipo de diseño.
Edificio de oficinas · ventana C0623_B_2 | Planos de arquitectura del edificio de oficinas; Planos de arquitectura del edificio de oficinas | Aluminio y acristalamiento 6+12A+6 | 0.6 × 0.045 × 2.3 | 287.05 | 289.35 | 0.0621 | office_0219 | 0.126303 | 0.600537 | 2.3 | 3.021 | 0.0620997 | office | Edificio de oficinas | {"name":"Aluminio y acristalamiento 6+12A+6","source":"ARQ-OF-20260710 · A109 / p. 11","status":"known"} | {"documented":[{"label":"Anchura del hueco","value":0.6,"unit":"m","source":"ARQ-OF-20260710 · Arquitectura A101 / p. 3; Carpinterías A108 / p. 10, A109 / p. 11","status":"documentado"},{"label":"Altura del hueco","value":2.3,"unit":"m","source":"ARQ-OF-20260710 · Arquitectura A101 / p. 3; Carpinterías A108 / p. 10, A109 / p. 11","status":"documentado"},{"label":"Altura de antepecho","value":1.1,"unit":"m","source":"ARQ-OF-20260710 · Arquitectura A101 / p. 3; Carpinterías A108 / p. 10, A109 / p. 11","status":"documentado"}],"geometry":[{"label":"Dimensiones de la caja local del elemento (X, Y, Z)","value":"0.6 × 0.045 × 2.3","unit":"m","source":"Malla triangulada del elemento en ejes locales del edificio","status":"derivado"},{"label":"Cota mínima absoluta de la malla","value":287.05,"unit":"m","source":"Malla de proyecto y origen altimétrico 285 m","status":"derivado"},{"label":"Cota máxima absoluta de la malla","value":289.35,"unit":"m","source":"Malla de proyecto y origen altimétrico 285 m","status":"derivado"},{"label":"Volumen geométrico bruto","value":0.0621,"unit":"m³","source":"Malla cerrada del elemento","status":"derivado"},{"label":"Espesor utilizado para representación","value":0.045,"unit":"m","source":"Hipótesis de visualización, no dimensión de fabricación","status":"provisional"}],"notes":["Las dimensiones documentadas proceden de anotaciones o cuadros; la caja y el volumen se calculan a partir de la malla.","El volumen es exclusivamente geométrico y bruto; no representa una medición neta de material ni una cantidad de compra."]} | {"documentId":"ARQ-OF-20260710","title":"Planos de arquitectura del edificio de oficinas","date":"2026-07-10","sheet":"Arquitectura A101 / p. 3; Carpinterías A108 / p. 10, A109 / p. 11"} | ["Posición deducida de las cadenas de cotas en planta; diferencia de 100 mm al final de la cadena sur pendiente de revisión. Antepecho de +1,100 m según alzado A106.","El plano general de 2026-07-31 mantiene el edificio de oficinas de 200 m², mientras documentación anterior indica su supresión. Se conserva lo dibujado, pendiente de confirmación de la propiedad y del equipo de diseño.","Elemento representado por un sólido cerrado único; perfiles de marco y hoja sin detalle de fabricación.","Registro de líneas del PDF general, envolvente de 20 × 10 m; eje local 1 al norte y acceso del lado A al oeste. Estimación de trabajo de implantación de ±0,15 m, pendiente de CAD; no constituye una precisión topográfica garantizada."] | {"horizontalStatus":"derivado","verticalStatus":"provisional","baseElevationM":285.95,"note":"Registro de líneas del PDF general, envolvente de 20 × 10 m; eje local 1 al norte y acceso del lado A al oeste. Estimación de trabajo de implantación de ±0,15 m, pendiente de CAD; no constituye una precisión topográfica garantizada."} | {"Pset_WindowCommon":{"IsExternal":{"value":true,"source":"ARQ-OF-20260710 · A101, A103 y alzados; elemento de la envolvente exterior identificada en planta","status":"known"}}} | {"boundingBoxM":{"min":[25.053479,75.021975,2.05],"max":[25.179782,75.622512,4.35]},"extentsM":[0.126303,0.600537,2.3],"meshSurfaceM2":3.020997,"meshVolumeM3":0.0621,"closedSolid":true,"basis":"Geometría triangulada releída del IFC; envolventes y magnitudes no contractuales."} | {"material":true,"document":true,"quantities":true,"containerGuid":"3ztlotcerHPueDgxP84R6z","containerName":"Planta baja"} | {"profileId":"glass_aluminum","name":"Carpintería acristalada · azul gris","materialName":"Aluminio y acristalamiento 6+12A+6","physicalMaterialStatus":"known","physicalMaterialSource":"ARQ-OF-20260710 · A109 / p. 11","appearanceStatus":"criterio_visual","appearanceBasis":"Composición 6+12A+6 documentada. Transparencia gráfica aplicada al objeto completo; marco y vidrio aún comparten malla.","note":"La apariencia gráfica no modifica ni confirma la especificación física del material."} | {"elementId":"office_0219","ifcGuid":"3ml0GdUAzVP96chaTvuzFb","ifcClass":"IfcWindow","buildingId":"office","buildingName":"Edificio de oficinas","sourceDocumentId":"ARQ-OF-20260710","sourceRepresentationKind":"documentary_mesh"} | {"profileId":"glass_aluminum","name":"Carpintería acristalada · azul gris","status":"criterio_visual","basis":"Composición 6+12A+6 documentada. Transparencia gráfica aplicada al objeto completo; marco y vidrio aún comparten malla.","physicalMaterialUnchanged":true} | ARQ-OF-20260710 · Arquitectura A101 / p. 3; Carpinterías A108 / p. 10, A109 / p. 11 | Ventana | 0.6 | 1.1 | Posición deducida de las cadenas de cotas en planta; diferencia de 100 mm al final de la cadena sur pendiente de revisión. Antepecho de +1,100 m según alzado A106. | Registro de líneas del PDF general, envolvente de 20 × 10 m; eje local 1 al norte y acceso del lado A al oeste. Estimación de trabajo de implantación de ±0,15 m, pendiente de CAD; no constituye una precisión topográfica garantizada. | ARQ-OF-20260710 · A109 / p. 11 | 285.95 | Carpintería acristalada · azul gris | glass_aluminum | [0.560784,0.682353,0.721569] | 0.2 | 0.1 | Composición 6+12A+6 documentada. Transparencia gráfica aplicada al objeto completo; marco y vidrio aún comparten malla. | El plano general de 2026-07-31 mantiene el edificio de oficinas de 200 m², mientras documentación anterior indica su supresión. Se conserva lo dibujado, pendiente de confirmación de la propiedad y del equipo de diseño.
Edificio de oficinas · ventana C0623_B_3 | Planos de arquitectura del edificio de oficinas; Planos de arquitectura del edificio de oficinas | Aluminio y acristalamiento 6+12A+6 | 0.6 × 0.045 × 2.3 | 287.05 | 289.35 | 0.0621 | office_0220 | 0.126303 | 0.600537 | 2.3 | 3.021 | 0.0620997 | office | Edificio de oficinas | {"name":"Aluminio y acristalamiento 6+12A+6","source":"ARQ-OF-20260710 · A109 / p. 11","status":"known"} | {"documented":[{"label":"Anchura del hueco","value":0.6,"unit":"m","source":"ARQ-OF-20260710 · Arquitectura A101 / p. 3; Carpinterías A108 / p. 10, A109 / p. 11","status":"documentado"},{"label":"Altura del hueco","value":2.3,"unit":"m","source":"ARQ-OF-20260710 · Arquitectura A101 / p. 3; Carpinterías A108 / p. 10, A109 / p. 11","status":"documentado"},{"label":"Altura de antepecho","value":1.1,"unit":"m","source":"ARQ-OF-20260710 · Arquitectura A101 / p. 3; Carpinterías A108 / p. 10, A109 / p. 11","status":"documentado"}],"geometry":[{"label":"Dimensiones de la caja local del elemento (X, Y, Z)","value":"0.6 × 0.045 × 2.3","unit":"m","source":"Malla triangulada del elemento en ejes locales del edificio","status":"derivado"},{"label":"Cota mínima absoluta de la malla","value":287.05,"unit":"m","source":"Malla de proyecto y origen altimétrico 285 m","status":"derivado"},{"label":"Cota máxima absoluta de la malla","value":289.35,"unit":"m","source":"Malla de proyecto y origen altimétrico 285 m","status":"derivado"},{"label":"Volumen geométrico bruto","value":0.0621,"unit":"m³","source":"Malla cerrada del elemento","status":"derivado"},{"label":"Espesor utilizado para representación","value":0.045,"unit":"m","source":"Hipótesis de visualización, no dimensión de fabricación","status":"provisional"}],"notes":["Las dimensiones documentadas proceden de anotaciones o cuadros; la caja y el volumen se calculan a partir de la malla.","El volumen es exclusivamente geométrico y bruto; no representa una medición neta de material ni una cantidad de compra."]} | {"documentId":"ARQ-OF-20260710","title":"Planos de arquitectura del edificio de oficinas","date":"2026-07-10","sheet":"Arquitectura A101 / p. 3; Carpinterías A108 / p. 10, A109 / p. 11"} | ["Posición deducida de las cadenas de cotas en planta; diferencia de 100 mm al final de la cadena sur pendiente de revisión. Antepecho de +1,100 m según alzado A106.","El plano general de 2026-07-31 mantiene el edificio de oficinas de 200 m², mientras documentación anterior indica su supresión. Se conserva lo dibujado, pendiente de confirmación de la propiedad y del equipo de diseño.","Elemento representado por un sólido cerrado único; perfiles de marco y hoja sin detalle de fabricación.","Registro de líneas del PDF general, envolvente de 20 × 10 m; eje local 1 al norte y acceso del lado A al oeste. Estimación de trabajo de implantación de ±0,15 m, pendiente de CAD; no constituye una precisión topográfica garantizada."] | {"horizontalStatus":"derivado","verticalStatus":"provisional","baseElevationM":285.95,"note":"Registro de líneas del PDF general, envolvente de 20 × 10 m; eje local 1 al norte y acceso del lado A al oeste. Estimación de trabajo de implantación de ±0,15 m, pendiente de CAD; no constituye una precisión topográfica garantizada."} | {"Pset_WindowCommon":{"IsExternal":{"value":true,"source":"ARQ-OF-20260710 · A101, A103 y alzados; elemento de la envolvente exterior identificada en planta","status":"known"}}} | {"boundingBoxM":{"min":[24.71297,72.545273,2.05],"max":[24.839273,73.14581,4.35]},"extentsM":[0.126303,0.600537,2.3],"meshSurfaceM2":3.020997,"meshVolumeM3":0.0621,"closedSolid":true,"basis":"Geometría triangulada releída del IFC; envolventes y magnitudes no contractuales."} | {"material":true,"document":true,"quantities":true,"containerGuid":"3ztlotcerHPueDgxP84R6z","containerName":"Planta baja"} | {"profileId":"glass_aluminum","name":"Carpintería acristalada · azul gris","materialName":"Aluminio y acristalamiento 6+12A+6","physicalMaterialStatus":"known","physicalMaterialSource":"ARQ-OF-20260710 · A109 / p. 11","appearanceStatus":"criterio_visual","appearanceBasis":"Composición 6+12A+6 documentada. Transparencia gráfica aplicada al objeto completo; marco y vidrio aún comparten malla.","note":"La apariencia gráfica no modifica ni confirma la especificación física del material."} | {"elementId":"office_0220","ifcGuid":"0H11RMzYbQeB6haxs4HSD5","ifcClass":"IfcWindow","buildingId":"office","buildingName":"Edificio de oficinas","sourceDocumentId":"ARQ-OF-20260710","sourceRepresentationKind":"documentary_mesh"} | {"profileId":"glass_aluminum","name":"Carpintería acristalada · azul gris","status":"criterio_visual","basis":"Composición 6+12A+6 documentada. Transparencia gráfica aplicada al objeto completo; marco y vidrio aún comparten malla.","physicalMaterialUnchanged":true} | ARQ-OF-20260710 · Arquitectura A101 / p. 3; Carpinterías A108 / p. 10, A109 / p. 11 | Ventana | 0.6 | 1.1 | Posición deducida de las cadenas de cotas en planta; diferencia de 100 mm al final de la cadena sur pendiente de revisión. Antepecho de +1,100 m según alzado A106. | Registro de líneas del PDF general, envolvente de 20 × 10 m; eje local 1 al norte y acceso del lado A al oeste. Estimación de trabajo de implantación de ±0,15 m, pendiente de CAD; no constituye una precisión topográfica garantizada. | ARQ-OF-20260710 · A109 / p. 11 | 285.95 | Carpintería acristalada · azul gris | glass_aluminum | [0.560784,0.682353,0.721569] | 0.2 | 0.1 | Composición 6+12A+6 documentada. Transparencia gráfica aplicada al objeto completo; marco y vidrio aún comparten malla. | El plano general de 2026-07-31 mantiene el edificio de oficinas de 200 m², mientras documentación anterior indica su supresión. Se conserva lo dibujado, pendiente de confirmación de la propiedad y del equipo de diseño.
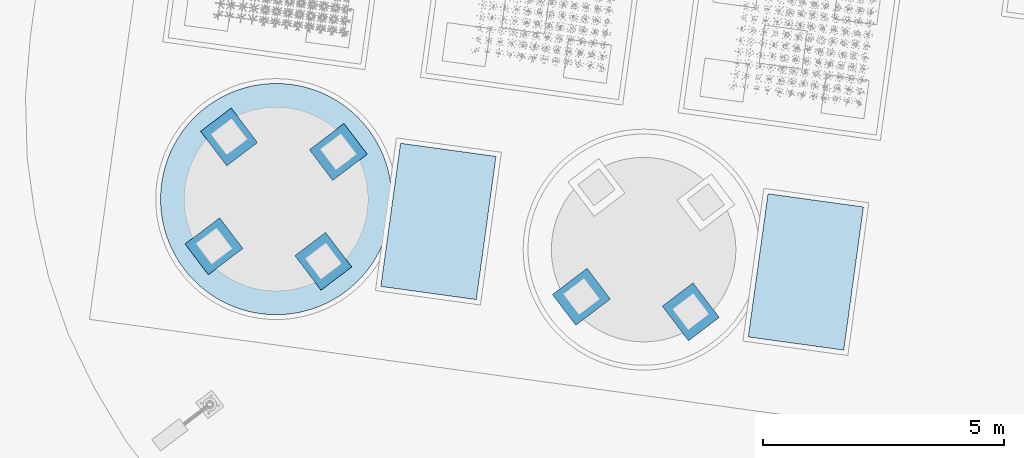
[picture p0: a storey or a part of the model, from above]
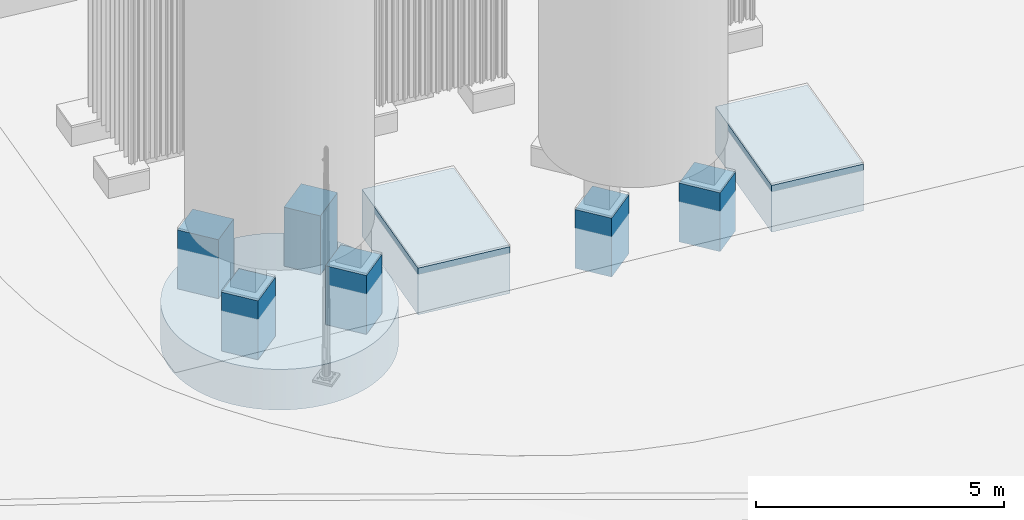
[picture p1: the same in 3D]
Properties of the parts of a building model (IFC4), part 133 of 134

# IfcWindow (22)
Name | Document | Material = JH_Trazabilidad, Material = name | Dimensiones de la caja local del elemento (X, Y, Z) | Cota mínima absoluta de la malla (m) | Cota máxima absoluta de la malla (m) | Volumen geométrico bruto (m3) = Volumen geométrico (m³) | Reference = Identificador del elemento = Identificador | ExtensionX (m) | ExtensionY (m) | ExtensionZ (m) = Altura del hueco (m) = Altura del hueco (m) | SuperficieDeLaMalla (m2) | VolumenGeometrico (m3) | buildingId | buildingName = Edificio | material | dimensions | JH_InformacionBIM, source = DocumentoFuente | issues = IncidenciasPendientes | positioning = PosicionYEstado | commonProperties | geometryMetrics | ifcAssociations | materialAppearance | visualizationIdentity | appearance | Planos de referencia | Tipo de carpintería | Anchura del hueco (m) = Anchura del hueco (m) | Altura de antepecho (m) = Altura de antepecho (m) | Comprobación pendiente | Estado de la implantación | Referencia del material = JH_EvidenciaDeMaterial, source | Cota de planta baja terminada (m) | Acabado de visualización = Acabado | Perfil | ColorRGB | Rugosidad | Metallicidad | Referencia | Discrepancia entre versiones
Edificio de oficinas · ventana C0923_A_1 | Planos de arquitectura del edificio de oficinas; Planos de arquitectura del edificio de oficinas | Aluminio y acristalamiento 6+12A+6 | 0.9 × 0.045 × 2.3 | 287.05 | 289.35 | 0.09315 | office_0221 | 0.167164 | 0.897742 | 2.3 | 4.428 | 0.0931497 | office | Edificio de oficinas | {"name":"Aluminio y acristalamiento 6+12A+6","source":"ARQ-OF-20260710 · A109 / p. 11","status":"known"} | {"documented":[{"label":"Anchura del hueco","value":0.9,"unit":"m","source":"ARQ-OF-20260710 · Arquitectura A101 / p. 3; Carpinterías A108 / p. 10, A109 / p. 11","status":"documentado"},{"label":"Altura del hueco","value":2.3,"unit":"m","source":"ARQ-OF-20260710 · Arquitectura A101 / p. 3; Carpinterías A108 / p. 10, A109 / p. 11","status":"documentado"},{"label":"Altura de antepecho","value":1.1,"unit":"m","source":"ARQ-OF-20260710 · Arquitectura A101 / p. 3; Carpinterías A108 / p. 10, A109 / p. 11","status":"documentado"}],"geometry":[{"label":"Dimensiones de la caja local del elemento (X, Y, Z)","value":"0.9 × 0.045 × 2.3","unit":"m","source":"Malla triangulada del elemento en ejes locales del edificio","status":"derivado"},{"label":"Cota mínima absoluta de la malla","value":287.05,"unit":"m","source":"Malla de proyecto y origen altimétrico 285 m","status":"derivado"},{"label":"Cota máxima absoluta de la malla","value":289.35,"unit":"m","source":"Malla de proyecto y origen altimétrico 285 m","status":"derivado"},{"label":"Volumen geométrico bruto","value":0.09315,"unit":"m³","source":"Malla cerrada del elemento","status":"derivado"},{"label":"Espesor utilizado para representación","value":0.045,"unit":"m","source":"Hipótesis de visualización, no dimensión de fabricación","status":"provisional"}],"notes":["Las dimensiones documentadas proceden de anotaciones o cuadros; la caja y el volumen se calculan a partir de la malla.","El volumen es exclusivamente geométrico y bruto; no representa una medición neta de material ni una cantidad de compra."]} | {"documentId":"ARQ-OF-20260710","title":"Planos de arquitectura del edificio de oficinas","date":"2026-07-10","sheet":"Arquitectura A101 / p. 3; Carpinterías A108 / p. 10, A109 / p. 11"} | ["Posición deducida de las cadenas de cotas en planta; diferencia de 100 mm al final de la cadena sur pendiente de revisión. Antepecho de +1,100 m según alzado A106.","El plano general de 2026-07-31 mantiene el edificio de oficinas de 200 m², mientras documentación anterior indica su supresión. Se conserva lo dibujado, pendiente de confirmación de la propiedad y del equipo de diseño.","Elemento representado por un sólido cerrado único; perfiles de marco y hoja sin detalle de fabricación.","Registro de líneas del PDF general, envolvente de 20 × 10 m; eje local 1 al norte y acceso del lado A al oeste. Estimación de trabajo de implantación de ±0,15 m, pendiente de CAD; no constituye una precisión topográfica garantizada."] | {"horizontalStatus":"derivado","verticalStatus":"provisional","baseElevationM":285.95,"note":"Registro de líneas del PDF general, envolvente de 20 × 10 m; eje local 1 al norte y acceso del lado A al oeste. Estimación de trabajo de implantación de ±0,15 m, pendiente de CAD; no constituye una precisión topográfica garantizada."} | {"Pset_WindowCommon":{"IsExternal":{"value":true,"source":"ARQ-OF-20260710 · A101, A103 y alzados; elemento de la envolvente exterior identificada en planta","status":"known"}}} | {"boundingBoxM":{"min":[16.809,87.006592,2.05],"max":[16.976164,87.904334,4.35]},"extentsM":[0.167164,0.897742,2.3],"meshSurfaceM2":4.428,"meshVolumeM3":0.09315,"closedSolid":true,"basis":"Geometría triangulada releída del IFC; envolventes y magnitudes no contractuales."} | {"material":true,"document":true,"quantities":true,"containerGuid":"3ztlotcerHPueDgxP84R6z","containerName":"Planta baja"} | {"profileId":"glass_aluminum","name":"Carpintería acristalada · azul gris","materialName":"Aluminio y acristalamiento 6+12A+6","physicalMaterialStatus":"known","physicalMaterialSource":"ARQ-OF-20260710 · A109 / p. 11","appearanceStatus":"criterio_visual","appearanceBasis":"Composición 6+12A+6 documentada. Transparencia gráfica aplicada al objeto completo; marco y vidrio aún comparten malla.","note":"La apariencia gráfica no modifica ni confirma la especificación física del material."} | {"elementId":"office_0221","ifcGuid":"32RDEG7brGjfM0qaDZYnGE","ifcClass":"IfcWindow","buildingId":"office","buildingName":"Edificio de oficinas","sourceDocumentId":"ARQ-OF-20260710","sourceRepresentationKind":"documentary_mesh"} | {"profileId":"glass_aluminum","name":"Carpintería acristalada · azul gris","status":"criterio_visual","basis":"Composición 6+12A+6 documentada. Transparencia gráfica aplicada al objeto completo; marco y vidrio aún comparten malla.","physicalMaterialUnchanged":true} | ARQ-OF-20260710 · Arquitectura A101 / p. 3; Carpinterías A108 / p. 10, A109 / p. 11 | Ventana | 0.9 | 1.1 | Posición deducida de las cadenas de cotas en planta; diferencia de 100 mm al final de la cadena sur pendiente de revisión. Antepecho de +1,100 m según alzado A106. | Registro de líneas del PDF general, envolvente de 20 × 10 m; eje local 1 al norte y acceso del lado A al oeste. Estimación de trabajo de implantación de ±0,15 m, pendiente de CAD; no constituye una precisión topográfica garantizada. | ARQ-OF-20260710 · A109 / p. 11 | 285.95 | Carpintería acristalada · azul gris | glass_aluminum | [0.560784,0.682353,0.721569] | 0.2 | 0.1 | Composición 6+12A+6 documentada. Transparencia gráfica aplicada al objeto completo; marco y vidrio aún comparten malla. | El plano general de 2026-07-31 mantiene el edificio de oficinas de 200 m², mientras documentación anterior indica su supresión. Se conserva lo dibujado, pendiente de confirmación de la propiedad y del equipo de diseño.
Edificio de oficinas · ventana C0923_A_2 | Planos de arquitectura del edificio de oficinas; Planos de arquitectura del edificio de oficinas | Aluminio y acristalamiento 6+12A+6 | 0.9 × 0.045 × 2.3 | 287.05 | 289.35 | 0.09315 | office_0222 | 0.167165 | 0.897742 | 2.3 | 4.428 | 0.0931508 | office | Edificio de oficinas | {"name":"Aluminio y acristalamiento 6+12A+6","source":"ARQ-OF-20260710 · A109 / p. 11","status":"known"} | {"documented":[{"label":"Anchura del hueco","value":0.9,"unit":"m","source":"ARQ-OF-20260710 · Arquitectura A101 / p. 3; Carpinterías A108 / p. 10, A109 / p. 11","status":"documentado"},{"label":"Altura del hueco","value":2.3,"unit":"m","source":"ARQ-OF-20260710 · Arquitectura A101 / p. 3; Carpinterías A108 / p. 10, A109 / p. 11","status":"documentado"},{"label":"Altura de antepecho","value":1.1,"unit":"m","source":"ARQ-OF-20260710 · Arquitectura A101 / p. 3; Carpinterías A108 / p. 10, A109 / p. 11","status":"documentado"}],"geometry":[{"label":"Dimensiones de la caja local del elemento (X, Y, Z)","value":"0.9 × 0.045 × 2.3","unit":"m","source":"Malla triangulada del elemento en ejes locales del edificio","status":"derivado"},{"label":"Cota mínima absoluta de la malla","value":287.05,"unit":"m","source":"Malla de proyecto y origen altimétrico 285 m","status":"derivado"},{"label":"Cota máxima absoluta de la malla","value":289.35,"unit":"m","source":"Malla de proyecto y origen altimétrico 285 m","status":"derivado"},{"label":"Volumen geométrico bruto","value":0.09315,"unit":"m³","source":"Malla cerrada del elemento","status":"derivado"},{"label":"Espesor utilizado para representación","value":0.045,"unit":"m","source":"Hipótesis de visualización, no dimensión de fabricación","status":"provisional"}],"notes":["Las dimensiones documentadas proceden de anotaciones o cuadros; la caja y el volumen se calculan a partir de la malla.","El volumen es exclusivamente geométrico y bruto; no representa una medición neta de material ni una cantidad de compra."]} | {"documentId":"ARQ-OF-20260710","title":"Planos de arquitectura del edificio de oficinas","date":"2026-07-10","sheet":"Arquitectura A101 / p. 3; Carpinterías A108 / p. 10, A109 / p. 11"} | ["Posición deducida de las cadenas de cotas en planta; diferencia de 100 mm al final de la cadena sur pendiente de revisión. Antepecho de +1,100 m según alzado A106.","El plano general de 2026-07-31 mantiene el edificio de oficinas de 200 m², mientras documentación anterior indica su supresión. Se conserva lo dibujado, pendiente de confirmación de la propiedad y del equipo de diseño.","Elemento representado por un sólido cerrado único; perfiles de marco y hoja sin detalle de fabricación.","Registro de líneas del PDF general, envolvente de 20 × 10 m; eje local 1 al norte y acceso del lado A al oeste. Estimación de trabajo de implantación de ±0,15 m, pendiente de CAD; no constituye una precisión topográfica garantizada."] | {"horizontalStatus":"derivado","verticalStatus":"provisional","baseElevationM":285.95,"note":"Registro de líneas del PDF general, envolvente de 20 × 10 m; eje local 1 al norte y acceso del lado A al oeste. Estimación de trabajo de implantación de ±0,15 m, pendiente de CAD; no constituye una precisión topográfica garantizada."} | {"Pset_WindowCommon":{"IsExternal":{"value":true,"source":"ARQ-OF-20260710 · A101, A103 y alzados; elemento de la envolvente exterior identificada en planta","status":"known"}}} | {"boundingBoxM":{"min":[16.563832,85.223366,2.05],"max":[16.730997,86.121108,4.35]},"extentsM":[0.167165,0.897742,2.3],"meshSurfaceM2":4.428002,"meshVolumeM3":0.093151,"closedSolid":true,"basis":"Geometría triangulada releída del IFC; envolventes y magnitudes no contractuales."} | {"material":true,"document":true,"quantities":true,"containerGuid":"3ztlotcerHPueDgxP84R6z","containerName":"Planta baja"} | {"profileId":"glass_aluminum","name":"Carpintería acristalada · azul gris","materialName":"Aluminio y acristalamiento 6+12A+6","physicalMaterialStatus":"known","physicalMaterialSource":"ARQ-OF-20260710 · A109 / p. 11","appearanceStatus":"criterio_visual","appearanceBasis":"Composición 6+12A+6 documentada. Transparencia gráfica aplicada al objeto completo; marco y vidrio aún comparten malla.","note":"La apariencia gráfica no modifica ni confirma la especificación física del material."} | {"elementId":"office_0222","ifcGuid":"3xa04zoJTJCwPjdLqz9QsQ","ifcClass":"IfcWindow","buildingId":"office","buildingName":"Edificio de oficinas","sourceDocumentId":"ARQ-OF-20260710","sourceRepresentationKind":"documentary_mesh"} | {"profileId":"glass_aluminum","name":"Carpintería acristalada · azul gris","status":"criterio_visual","basis":"Composición 6+12A+6 documentada. Transparencia gráfica aplicada al objeto completo; marco y vidrio aún comparten malla.","physicalMaterialUnchanged":true} | ARQ-OF-20260710 · Arquitectura A101 / p. 3; Carpinterías A108 / p. 10, A109 / p. 11 | Ventana | 0.9 | 1.1 | Posición deducida de las cadenas de cotas en planta; diferencia de 100 mm al final de la cadena sur pendiente de revisión. Antepecho de +1,100 m según alzado A106. | Registro de líneas del PDF general, envolvente de 20 × 10 m; eje local 1 al norte y acceso del lado A al oeste. Estimación de trabajo de implantación de ±0,15 m, pendiente de CAD; no constituye una precisión topográfica garantizada. | ARQ-OF-20260710 · A109 / p. 11 | 285.95 | Carpintería acristalada · azul gris | glass_aluminum | [0.560784,0.682353,0.721569] | 0.2 | 0.1 | Composición 6+12A+6 documentada. Transparencia gráfica aplicada al objeto completo; marco y vidrio aún comparten malla. | El plano general de 2026-07-31 mantiene el edificio de oficinas de 200 m², mientras documentación anterior indica su supresión. Se conserva lo dibujado, pendiente de confirmación de la propiedad y del equipo de diseño.
Edificio de oficinas · ventana C0923_A_3 | Planos de arquitectura del edificio de oficinas; Planos de arquitectura del edificio de oficinas | Aluminio y acristalamiento 6+12A+6 | 0.9 × 0.045 × 2.3 | 287.05 | 289.35 | 0.09315 | office_0223 | 0.167165 | 0.897742 | 2.3 | 4.428 | 0.0931507 | office | Edificio de oficinas | {"name":"Aluminio y acristalamiento 6+12A+6","source":"ARQ-OF-20260710 · A109 / p. 11","status":"known"} | {"documented":[{"label":"Anchura del hueco","value":0.9,"unit":"m","source":"ARQ-OF-20260710 · Arquitectura A101 / p. 3; Carpinterías A108 / p. 10, A109 / p. 11","status":"documentado"},{"label":"Altura del hueco","value":2.3,"unit":"m","source":"ARQ-OF-20260710 · Arquitectura A101 / p. 3; Carpinterías A108 / p. 10, A109 / p. 11","status":"documentado"},{"label":"Altura de antepecho","value":1.1,"unit":"m","source":"ARQ-OF-20260710 · Arquitectura A101 / p. 3; Carpinterías A108 / p. 10, A109 / p. 11","status":"documentado"}],"geometry":[{"label":"Dimensiones de la caja local del elemento (X, Y, Z)","value":"0.9 × 0.045 × 2.3","unit":"m","source":"Malla triangulada del elemento en ejes locales del edificio","status":"derivado"},{"label":"Cota mínima absoluta de la malla","value":287.05,"unit":"m","source":"Malla de proyecto y origen altimétrico 285 m","status":"derivado"},{"label":"Cota máxima absoluta de la malla","value":289.35,"unit":"m","source":"Malla de proyecto y origen altimétrico 285 m","status":"derivado"},{"label":"Volumen geométrico bruto","value":0.09315,"unit":"m³","source":"Malla cerrada del elemento","status":"derivado"},{"label":"Espesor utilizado para representación","value":0.045,"unit":"m","source":"Hipótesis de visualización, no dimensión de fabricación","status":"provisional"}],"notes":["Las dimensiones documentadas proceden de anotaciones o cuadros; la caja y el volumen se calculan a partir de la malla.","El volumen es exclusivamente geométrico y bruto; no representa una medición neta de material ni una cantidad de compra."]} | {"documentId":"ARQ-OF-20260710","title":"Planos de arquitectura del edificio de oficinas","date":"2026-07-10","sheet":"Arquitectura A101 / p. 3; Carpinterías A108 / p. 10, A109 / p. 11"} | ["Posición deducida de las cadenas de cotas en planta; diferencia de 100 mm al final de la cadena sur pendiente de revisión. Antepecho de +1,100 m según alzado A106.","El plano general de 2026-07-31 mantiene el edificio de oficinas de 200 m², mientras documentación anterior indica su supresión. Se conserva lo dibujado, pendiente de confirmación de la propiedad y del equipo de diseño.","Elemento representado por un sólido cerrado único; perfiles de marco y hoja sin detalle de fabricación.","Registro de líneas del PDF general, envolvente de 20 × 10 m; eje local 1 al norte y acceso del lado A al oeste. Estimación de trabajo de implantación de ±0,15 m, pendiente de CAD; no constituye una precisión topográfica garantizada."] | {"horizontalStatus":"derivado","verticalStatus":"provisional","baseElevationM":285.95,"note":"Registro de líneas del PDF general, envolvente de 20 × 10 m; eje local 1 al norte y acceso del lado A al oeste. Estimación de trabajo de implantación de ±0,15 m, pendiente de CAD; no constituye una precisión topográfica garantizada."} | {"Pset_WindowCommon":{"IsExternal":{"value":true,"source":"ARQ-OF-20260710 · A101, A103 y alzados; elemento de la envolvente exterior identificada en planta","status":"known"}}} | {"boundingBoxM":{"min":[16.318665,83.440141,2.05],"max":[16.48583,84.337883,4.35]},"extentsM":[0.167165,0.897742,2.3],"meshSurfaceM2":4.428004,"meshVolumeM3":0.093151,"closedSolid":true,"basis":"Geometría triangulada releída del IFC; envolventes y magnitudes no contractuales."} | {"material":true,"document":true,"quantities":true,"containerGuid":"3ztlotcerHPueDgxP84R6z","containerName":"Planta baja"} | {"profileId":"glass_aluminum","name":"Carpintería acristalada · azul gris","materialName":"Aluminio y acristalamiento 6+12A+6","physicalMaterialStatus":"known","physicalMaterialSource":"ARQ-OF-20260710 · A109 / p. 11","appearanceStatus":"criterio_visual","appearanceBasis":"Composición 6+12A+6 documentada. Transparencia gráfica aplicada al objeto completo; marco y vidrio aún comparten malla.","note":"La apariencia gráfica no modifica ni confirma la especificación física del material."} | {"elementId":"office_0223","ifcGuid":"3HE9r64lvMsxgCFMmfOXZE","ifcClass":"IfcWindow","buildingId":"office","buildingName":"Edificio de oficinas","sourceDocumentId":"ARQ-OF-20260710","sourceRepresentationKind":"documentary_mesh"} | {"profileId":"glass_aluminum","name":"Carpintería acristalada · azul gris","status":"criterio_visual","basis":"Composición 6+12A+6 documentada. Transparencia gráfica aplicada al objeto completo; marco y vidrio aún comparten malla.","physicalMaterialUnchanged":true} | ARQ-OF-20260710 · Arquitectura A101 / p. 3; Carpinterías A108 / p. 10, A109 / p. 11 | Ventana | 0.9 | 1.1 | Posición deducida de las cadenas de cotas en planta; diferencia de 100 mm al final de la cadena sur pendiente de revisión. Antepecho de +1,100 m según alzado A106. | Registro de líneas del PDF general, envolvente de 20 × 10 m; eje local 1 al norte y acceso del lado A al oeste. Estimación de trabajo de implantación de ±0,15 m, pendiente de CAD; no constituye una precisión topográfica garantizada. | ARQ-OF-20260710 · A109 / p. 11 | 285.95 | Carpintería acristalada · azul gris | glass_aluminum | [0.560784,0.682353,0.721569] | 0.2 | 0.1 | Composición 6+12A+6 documentada. Transparencia gráfica aplicada al objeto completo; marco y vidrio aún comparten malla. | El plano general de 2026-07-31 mantiene el edificio de oficinas de 200 m², mientras documentación anterior indica su supresión. Se conserva lo dibujado, pendiente de confirmación de la propiedad y del equipo de diseño.
Edificio de oficinas · ventana C0923_A_4 | Planos de arquitectura del edificio de oficinas; Planos de arquitectura del edificio de oficinas | Aluminio y acristalamiento 6+12A+6 | 0.9 × 0.045 × 2.3 | 287.05 | 289.35 | 0.09315 | office_0224 | 0.167165 | 0.897741 | 2.3 | 4.428 | 0.0931506 | office | Edificio de oficinas | {"name":"Aluminio y acristalamiento 6+12A+6","source":"ARQ-OF-20260710 · A109 / p. 11","status":"known"} | {"documented":[{"label":"Anchura del hueco","value":0.9,"unit":"m","source":"ARQ-OF-20260710 · Arquitectura A101 / p. 3; Carpinterías A108 / p. 10, A109 / p. 11","status":"documentado"},{"label":"Altura del hueco","value":2.3,"unit":"m","source":"ARQ-OF-20260710 · Arquitectura A101 / p. 3; Carpinterías A108 / p. 10, A109 / p. 11","status":"documentado"},{"label":"Altura de antepecho","value":1.1,"unit":"m","source":"ARQ-OF-20260710 · Arquitectura A101 / p. 3; Carpinterías A108 / p. 10, A109 / p. 11","status":"documentado"}],"geometry":[{"label":"Dimensiones de la caja local del elemento (X, Y, Z)","value":"0.9 × 0.045 × 2.3","unit":"m","source":"Malla triangulada del elemento en ejes locales del edificio","status":"derivado"},{"label":"Cota mínima absoluta de la malla","value":287.05,"unit":"m","source":"Malla de proyecto y origen altimétrico 285 m","status":"derivado"},{"label":"Cota máxima absoluta de la malla","value":289.35,"unit":"m","source":"Malla de proyecto y origen altimétrico 285 m","status":"derivado"},{"label":"Volumen geométrico bruto","value":0.09315,"unit":"m³","source":"Malla cerrada del elemento","status":"derivado"},{"label":"Espesor utilizado para representación","value":0.045,"unit":"m","source":"Hipótesis de visualización, no dimensión de fabricación","status":"provisional"}],"notes":["Las dimensiones documentadas proceden de anotaciones o cuadros; la caja y el volumen se calculan a partir de la malla.","El volumen es exclusivamente geométrico y bruto; no representa una medición neta de material ni una cantidad de compra."]} | {"documentId":"ARQ-OF-20260710","title":"Planos de arquitectura del edificio de oficinas","date":"2026-07-10","sheet":"Arquitectura A101 / p. 3; Carpinterías A108 / p. 10, A109 / p. 11"} | ["Posición deducida de las cadenas de cotas en planta; diferencia de 100 mm al final de la cadena sur pendiente de revisión. Antepecho de +1,100 m según alzado A106.","El plano general de 2026-07-31 mantiene el edificio de oficinas de 200 m², mientras documentación anterior indica su supresión. Se conserva lo dibujado, pendiente de confirmación de la propiedad y del equipo de diseño.","Elemento representado por un sólido cerrado único; perfiles de marco y hoja sin detalle de fabricación.","Registro de líneas del PDF general, envolvente de 20 × 10 m; eje local 1 al norte y acceso del lado A al oeste. Estimación de trabajo de implantación de ±0,15 m, pendiente de CAD; no constituye una precisión topográfica garantizada."] | {"horizontalStatus":"derivado","verticalStatus":"provisional","baseElevationM":285.95,"note":"Registro de líneas del PDF general, envolvente de 20 × 10 m; eje local 1 al norte y acceso del lado A al oeste. Estimación de trabajo de implantación de ±0,15 m, pendiente de CAD; no constituye una precisión topográfica garantizada."} | {"Pset_WindowCommon":{"IsExternal":{"value":true,"source":"ARQ-OF-20260710 · A101, A103 y alzados; elemento de la envolvente exterior identificada en planta","status":"known"}}} | {"boundingBoxM":{"min":[16.073498,81.656916,2.05],"max":[16.240663,82.554657,4.35]},"extentsM":[0.167165,0.897741,2.3],"meshSurfaceM2":4.427999,"meshVolumeM3":0.093151,"closedSolid":true,"basis":"Geometría triangulada releída del IFC; envolventes y magnitudes no contractuales."} | {"material":true,"document":true,"quantities":true,"containerGuid":"3ztlotcerHPueDgxP84R6z","containerName":"Planta baja"} | {"profileId":"glass_aluminum","name":"Carpintería acristalada · azul gris","materialName":"Aluminio y acristalamiento 6+12A+6","physicalMaterialStatus":"known","physicalMaterialSource":"ARQ-OF-20260710 · A109 / p. 11","appearanceStatus":"criterio_visual","appearanceBasis":"Composición 6+12A+6 documentada. Transparencia gráfica aplicada al objeto completo; marco y vidrio aún comparten malla.","note":"La apariencia gráfica no modifica ni confirma la especificación física del material."} | {"elementId":"office_0224","ifcGuid":"2bCszpv61GMhmmU3b4PuVO","ifcClass":"IfcWindow","buildingId":"office","buildingName":"Edificio de oficinas","sourceDocumentId":"ARQ-OF-20260710","sourceRepresentationKind":"documentary_mesh"} | {"profileId":"glass_aluminum","name":"Carpintería acristalada · azul gris","status":"criterio_visual","basis":"Composición 6+12A+6 documentada. Transparencia gráfica aplicada al objeto completo; marco y vidrio aún comparten malla.","physicalMaterialUnchanged":true} | ARQ-OF-20260710 · Arquitectura A101 / p. 3; Carpinterías A108 / p. 10, A109 / p. 11 | Ventana | 0.9 | 1.1 | Posición deducida de las cadenas de cotas en planta; diferencia de 100 mm al final de la cadena sur pendiente de revisión. Antepecho de +1,100 m según alzado A106. | Registro de líneas del PDF general, envolvente de 20 × 10 m; eje local 1 al norte y acceso del lado A al oeste. Estimación de trabajo de implantación de ±0,15 m, pendiente de CAD; no constituye una precisión topográfica garantizada. | ARQ-OF-20260710 · A109 / p. 11 | 285.95 | Carpintería acristalada · azul gris | glass_aluminum | [0.560784,0.682353,0.721569] | 0.2 | 0.1 | Composición 6+12A+6 documentada. Transparencia gráfica aplicada al objeto completo; marco y vidrio aún comparten malla. | El plano general de 2026-07-31 mantiene el edificio de oficinas de 200 m², mientras documentación anterior indica su supresión. Se conserva lo dibujado, pendiente de confirmación de la propiedad y del equipo de diseño.
Edificio de oficinas · ventana C0923_A_5 | Planos de arquitectura del edificio de oficinas; Planos de arquitectura del edificio de oficinas | Aluminio y acristalamiento 6+12A+6 | 0.9 × 0.045 × 2.3 | 287.05 | 289.35 | 0.09315 | office_0225 | 0.167164 | 0.897742 | 2.3 | 4.428 | 0.0931497 | office | Edificio de oficinas | {"name":"Aluminio y acristalamiento 6+12A+6","source":"ARQ-OF-20260710 · A109 / p. 11","status":"known"} | {"documented":[{"label":"Anchura del hueco","value":0.9,"unit":"m","source":"ARQ-OF-20260710 · Arquitectura A101 / p. 3; Carpinterías A108 / p. 10, A109 / p. 11","status":"documentado"},{"label":"Altura del hueco","value":2.3,"unit":"m","source":"ARQ-OF-20260710 · Arquitectura A101 / p. 3; Carpinterías A108 / p. 10, A109 / p. 11","status":"documentado"},{"label":"Altura de antepecho","value":1.1,"unit":"m","source":"ARQ-OF-20260710 · Arquitectura A101 / p. 3; Carpinterías A108 / p. 10, A109 / p. 11","status":"documentado"}],"geometry":[{"label":"Dimensiones de la caja local del elemento (X, Y, Z)","value":"0.9 × 0.045 × 2.3","unit":"m","source":"Malla triangulada del elemento en ejes locales del edificio","status":"derivado"},{"label":"Cota mínima absoluta de la malla","value":287.05,"unit":"m","source":"Malla de proyecto y origen altimétrico 285 m","status":"derivado"},{"label":"Cota máxima absoluta de la malla","value":289.35,"unit":"m","source":"Malla de proyecto y origen altimétrico 285 m","status":"derivado"},{"label":"Volumen geométrico bruto","value":0.09315,"unit":"m³","source":"Malla cerrada del elemento","status":"derivado"},{"label":"Espesor utilizado para representación","value":0.045,"unit":"m","source":"Hipótesis de visualización, no dimensión de fabricación","status":"provisional"}],"notes":["Las dimensiones documentadas proceden de anotaciones o cuadros; la caja y el volumen se calculan a partir de la malla.","El volumen es exclusivamente geométrico y bruto; no representa una medición neta de material ni una cantidad de compra."]} | {"documentId":"ARQ-OF-20260710","title":"Planos de arquitectura del edificio de oficinas","date":"2026-07-10","sheet":"Arquitectura A101 / p. 3; Carpinterías A108 / p. 10, A109 / p. 11"} | ["Posición deducida de las cadenas de cotas en planta; diferencia de 100 mm al final de la cadena sur pendiente de revisión. Antepecho de +1,100 m según alzado A106.","El plano general de 2026-07-31 mantiene el edificio de oficinas de 200 m², mientras documentación anterior indica su supresión. Se conserva lo dibujado, pendiente de confirmación de la propiedad y del equipo de diseño.","Elemento representado por un sólido cerrado único; perfiles de marco y hoja sin detalle de fabricación.","Registro de líneas del PDF general, envolvente de 20 × 10 m; eje local 1 al norte y acceso del lado A al oeste. Estimación de trabajo de implantación de ±0,15 m, pendiente de CAD; no constituye una precisión topográfica garantizada."] | {"horizontalStatus":"derivado","verticalStatus":"provisional","baseElevationM":285.95,"note":"Registro de líneas del PDF general, envolvente de 20 × 10 m; eje local 1 al norte y acceso del lado A al oeste. Estimación de trabajo de implantación de ±0,15 m, pendiente de CAD; no constituye una precisión topográfica garantizada."} | {"Pset_WindowCommon":{"IsExternal":{"value":true,"source":"ARQ-OF-20260710 · A101, A103 y alzados; elemento de la envolvente exterior identificada en planta","status":"known"}}} | {"boundingBoxM":{"min":[15.828331,79.87369,2.05],"max":[15.995495,80.771432,4.35]},"extentsM":[0.167164,0.897742,2.3],"meshSurfaceM2":4.428,"meshVolumeM3":0.09315,"closedSolid":true,"basis":"Geometría triangulada releída del IFC; envolventes y magnitudes no contractuales."} | {"material":true,"document":true,"quantities":true,"containerGuid":"3ztlotcerHPueDgxP84R6z","containerName":"Planta baja"} | {"profileId":"glass_aluminum","name":"Carpintería acristalada · azul gris","materialName":"Aluminio y acristalamiento 6+12A+6","physicalMaterialStatus":"known","physicalMaterialSource":"ARQ-OF-20260710 · A109 / p. 11","appearanceStatus":"criterio_visual","appearanceBasis":"Composición 6+12A+6 documentada. Transparencia gráfica aplicada al objeto completo; marco y vidrio aún comparten malla.","note":"La apariencia gráfica no modifica ni confirma la especificación física del material."} | {"elementId":"office_0225","ifcGuid":"1vqLI74rDSZuwGqNooTyCR","ifcClass":"IfcWindow","buildingId":"office","buildingName":"Edificio de oficinas","sourceDocumentId":"ARQ-OF-20260710","sourceRepresentationKind":"documentary_mesh"} | {"profileId":"glass_aluminum","name":"Carpintería acristalada · azul gris","status":"criterio_visual","basis":"Composición 6+12A+6 documentada. Transparencia gráfica aplicada al objeto completo; marco y vidrio aún comparten malla.","physicalMaterialUnchanged":true} | ARQ-OF-20260710 · Arquitectura A101 / p. 3; Carpinterías A108 / p. 10, A109 / p. 11 | Ventana | 0.9 | 1.1 | Posición deducida de las cadenas de cotas en planta; diferencia de 100 mm al final de la cadena sur pendiente de revisión. Antepecho de +1,100 m según alzado A106. | Registro de líneas del PDF general, envolvente de 20 × 10 m; eje local 1 al norte y acceso del lado A al oeste. Estimación de trabajo de implantación de ±0,15 m, pendiente de CAD; no constituye una precisión topográfica garantizada. | ARQ-OF-20260710 · A109 / p. 11 | 285.95 | Carpintería acristalada · azul gris | glass_aluminum | [0.560784,0.682353,0.721569] | 0.2 | 0.1 | Composición 6+12A+6 documentada. Transparencia gráfica aplicada al objeto completo; marco y vidrio aún comparten malla. | El plano general de 2026-07-31 mantiene el edificio de oficinas de 200 m², mientras documentación anterior indica su supresión. Se conserva lo dibujado, pendiente de confirmación de la propiedad y del equipo de diseño.
Edificio de oficinas · ventana C0923_A_6 | Planos de arquitectura del edificio de oficinas; Planos de arquitectura del edificio de oficinas | Aluminio y acristalamiento 6+12A+6 | 0.9 × 0.045 × 2.3 | 287.05 | 289.35 | 0.09315 | office_0226 | 0.167164 | 0.897741 | 2.3 | 4.428 | 0.0931496 | office | Edificio de oficinas | {"name":"Aluminio y acristalamiento 6+12A+6","source":"ARQ-OF-20260710 · A109 / p. 11","status":"known"} | {"documented":[{"label":"Anchura del hueco","value":0.9,"unit":"m","source":"ARQ-OF-20260710 · Arquitectura A101 / p. 3; Carpinterías A108 / p. 10, A109 / p. 11","status":"documentado"},{"label":"Altura del hueco","value":2.3,"unit":"m","source":"ARQ-OF-20260710 · Arquitectura A101 / p. 3; Carpinterías A108 / p. 10, A109 / p. 11","status":"documentado"},{"label":"Altura de antepecho","value":1.1,"unit":"m","source":"ARQ-OF-20260710 · Arquitectura A101 / p. 3; Carpinterías A108 / p. 10, A109 / p. 11","status":"documentado"}],"geometry":[{"label":"Dimensiones de la caja local del elemento (X, Y, Z)","value":"0.9 × 0.045 × 2.3","unit":"m","source":"Malla triangulada del elemento en ejes locales del edificio","status":"derivado"},{"label":"Cota mínima absoluta de la malla","value":287.05,"unit":"m","source":"Malla de proyecto y origen altimétrico 285 m","status":"derivado"},{"label":"Cota máxima absoluta de la malla","value":289.35,"unit":"m","source":"Malla de proyecto y origen altimétrico 285 m","status":"derivado"},{"label":"Volumen geométrico bruto","value":0.09315,"unit":"m³","source":"Malla cerrada del elemento","status":"derivado"},{"label":"Espesor utilizado para representación","value":0.045,"unit":"m","source":"Hipótesis de visualización, no dimensión de fabricación","status":"provisional"}],"notes":["Las dimensiones documentadas proceden de anotaciones o cuadros; la caja y el volumen se calculan a partir de la malla.","El volumen es exclusivamente geométrico y bruto; no representa una medición neta de material ni una cantidad de compra."]} | {"documentId":"ARQ-OF-20260710","title":"Planos de arquitectura del edificio de oficinas","date":"2026-07-10","sheet":"Arquitectura A101 / p. 3; Carpinterías A108 / p. 10, A109 / p. 11"} | ["Posición deducida de las cadenas de cotas en planta; diferencia de 100 mm al final de la cadena sur pendiente de revisión. Antepecho de +1,100 m según alzado A106.","El plano general de 2026-07-31 mantiene el edificio de oficinas de 200 m², mientras documentación anterior indica su supresión. Se conserva lo dibujado, pendiente de confirmación de la propiedad y del equipo de diseño.","Elemento representado por un sólido cerrado único; perfiles de marco y hoja sin detalle de fabricación.","Registro de líneas del PDF general, envolvente de 20 × 10 m; eje local 1 al norte y acceso del lado A al oeste. Estimación de trabajo de implantación de ±0,15 m, pendiente de CAD; no constituye una precisión topográfica garantizada."] | {"horizontalStatus":"derivado","verticalStatus":"provisional","baseElevationM":285.95,"note":"Registro de líneas del PDF general, envolvente de 20 × 10 m; eje local 1 al norte y acceso del lado A al oeste. Estimación de trabajo de implantación de ±0,15 m, pendiente de CAD; no constituye una precisión topográfica garantizada."} | {"Pset_WindowCommon":{"IsExternal":{"value":true,"source":"ARQ-OF-20260710 · A101, A103 y alzados; elemento de la envolvente exterior identificada en planta","status":"known"}}} | {"boundingBoxM":{"min":[15.583164,78.090465,2.05],"max":[15.750328,78.988206,4.35]},"extentsM":[0.167164,0.897741,2.3],"meshSurfaceM2":4.427996,"meshVolumeM3":0.09315,"closedSolid":true,"basis":"Geometría triangulada releída del IFC; envolventes y magnitudes no contractuales."} | {"material":true,"document":true,"quantities":true,"containerGuid":"3ztlotcerHPueDgxP84R6z","containerName":"Planta baja"} | {"profileId":"glass_aluminum","name":"Carpintería acristalada · azul gris","materialName":"Aluminio y acristalamiento 6+12A+6","physicalMaterialStatus":"known","physicalMaterialSource":"ARQ-OF-20260710 · A109 / p. 11","appearanceStatus":"criterio_visual","appearanceBasis":"Composición 6+12A+6 documentada. Transparencia gráfica aplicada al objeto completo; marco y vidrio aún comparten malla.","note":"La apariencia gráfica no modifica ni confirma la especificación física del material."} | {"elementId":"office_0226","ifcGuid":"0zIglrv91OA9n9kJVSw9XO","ifcClass":"IfcWindow","buildingId":"office","buildingName":"Edificio de oficinas","sourceDocumentId":"ARQ-OF-20260710","sourceRepresentationKind":"documentary_mesh"} | {"profileId":"glass_aluminum","name":"Carpintería acristalada · azul gris","status":"criterio_visual","basis":"Composición 6+12A+6 documentada. Transparencia gráfica aplicada al objeto completo; marco y vidrio aún comparten malla.","physicalMaterialUnchanged":true} | ARQ-OF-20260710 · Arquitectura A101 / p. 3; Carpinterías A108 / p. 10, A109 / p. 11 | Ventana | 0.9 | 1.1 | Posición deducida de las cadenas de cotas en planta; diferencia de 100 mm al final de la cadena sur pendiente de revisión. Antepecho de +1,100 m según alzado A106. | Registro de líneas del PDF general, envolvente de 20 × 10 m; eje local 1 al norte y acceso del lado A al oeste. Estimación de trabajo de implantación de ±0,15 m, pendiente de CAD; no constituye una precisión topográfica garantizada. | ARQ-OF-20260710 · A109 / p. 11 | 285.95 | Carpintería acristalada · azul gris | glass_aluminum | [0.560784,0.682353,0.721569] | 0.2 | 0.1 | Composición 6+12A+6 documentada. Transparencia gráfica aplicada al objeto completo; marco y vidrio aún comparten malla. | El plano general de 2026-07-31 mantiene el edificio de oficinas de 200 m², mientras documentación anterior indica su supresión. Se conserva lo dibujado, pendiente de confirmación de la propiedad y del equipo de diseño.
Edificio de oficinas · ventana C0923_A_7 | Planos de arquitectura del edificio de oficinas; Planos de arquitectura del edificio de oficinas | Aluminio y acristalamiento 6+12A+6 | 0.9 × 0.045 × 2.3 | 287.05 | 289.35 | 0.09315 | office_0227 | 0.167164 | 0.897742 | 2.3 | 4.428 | 0.0931497 | office | Edificio de oficinas | {"name":"Aluminio y acristalamiento 6+12A+6","source":"ARQ-OF-20260710 · A109 / p. 11","status":"known"} | {"documented":[{"label":"Anchura del hueco","value":0.9,"unit":"m","source":"ARQ-OF-20260710 · Arquitectura A101 / p. 3; Carpinterías A108 / p. 10, A109 / p. 11","status":"documentado"},{"label":"Altura del hueco","value":2.3,"unit":"m","source":"ARQ-OF-20260710 · Arquitectura A101 / p. 3; Carpinterías A108 / p. 10, A109 / p. 11","status":"documentado"},{"label":"Altura de antepecho","value":1.1,"unit":"m","source":"ARQ-OF-20260710 · Arquitectura A101 / p. 3; Carpinterías A108 / p. 10, A109 / p. 11","status":"documentado"}],"geometry":[{"label":"Dimensiones de la caja local del elemento (X, Y, Z)","value":"0.9 × 0.045 × 2.3","unit":"m","source":"Malla triangulada del elemento en ejes locales del edificio","status":"derivado"},{"label":"Cota mínima absoluta de la malla","value":287.05,"unit":"m","source":"Malla de proyecto y origen altimétrico 285 m","status":"derivado"},{"label":"Cota máxima absoluta de la malla","value":289.35,"unit":"m","source":"Malla de proyecto y origen altimétrico 285 m","status":"derivado"},{"label":"Volumen geométrico bruto","value":0.09315,"unit":"m³","source":"Malla cerrada del elemento","status":"derivado"},{"label":"Espesor utilizado para representación","value":0.045,"unit":"m","source":"Hipótesis de visualización, no dimensión de fabricación","status":"provisional"}],"notes":["Las dimensiones documentadas proceden de anotaciones o cuadros; la caja y el volumen se calculan a partir de la malla.","El volumen es exclusivamente geométrico y bruto; no representa una medición neta de material ni una cantidad de compra."]} | {"documentId":"ARQ-OF-20260710","title":"Planos de arquitectura del edificio de oficinas","date":"2026-07-10","sheet":"Arquitectura A101 / p. 3; Carpinterías A108 / p. 10, A109 / p. 11"} | ["Posición deducida de las cadenas de cotas en planta; diferencia de 100 mm al final de la cadena sur pendiente de revisión. Antepecho de +1,100 m según alzado A106.","El plano general de 2026-07-31 mantiene el edificio de oficinas de 200 m², mientras documentación anterior indica su supresión. Se conserva lo dibujado, pendiente de confirmación de la propiedad y del equipo de diseño.","Elemento representado por un sólido cerrado único; perfiles de marco y hoja sin detalle de fabricación.","Registro de líneas del PDF general, envolvente de 20 × 10 m; eje local 1 al norte y acceso del lado A al oeste. Estimación de trabajo de implantación de ±0,15 m, pendiente de CAD; no constituye una precisión topográfica garantizada."] | {"horizontalStatus":"derivado","verticalStatus":"provisional","baseElevationM":285.95,"note":"Registro de líneas del PDF general, envolvente de 20 × 10 m; eje local 1 al norte y acceso del lado A al oeste. Estimación de trabajo de implantación de ±0,15 m, pendiente de CAD; no constituye una precisión topográfica garantizada."} | {"Pset_WindowCommon":{"IsExternal":{"value":true,"source":"ARQ-OF-20260710 · A101, A103 y alzados; elemento de la envolvente exterior identificada en planta","status":"known"}}} | {"boundingBoxM":{"min":[15.337997,76.307239,2.05],"max":[15.505161,77.204981,4.35]},"extentsM":[0.167164,0.897742,2.3],"meshSurfaceM2":4.428,"meshVolumeM3":0.09315,"closedSolid":true,"basis":"Geometría triangulada releída del IFC; envolventes y magnitudes no contractuales."} | {"material":true,"document":true,"quantities":true,"containerGuid":"3ztlotcerHPueDgxP84R6z","containerName":"Planta baja"} | {"profileId":"glass_aluminum","name":"Carpintería acristalada · azul gris","materialName":"Aluminio y acristalamiento 6+12A+6","physicalMaterialStatus":"known","physicalMaterialSource":"ARQ-OF-20260710 · A109 / p. 11","appearanceStatus":"criterio_visual","appearanceBasis":"Composición 6+12A+6 documentada. Transparencia gráfica aplicada al objeto completo; marco y vidrio aún comparten malla.","note":"La apariencia gráfica no modifica ni confirma la especificación física del material."} | {"elementId":"office_0227","ifcGuid":"22c22V9g1S_O5rjmwbb9bT","ifcClass":"IfcWindow","buildingId":"office","buildingName":"Edificio de oficinas","sourceDocumentId":"ARQ-OF-20260710","sourceRepresentationKind":"documentary_mesh"} | {"profileId":"glass_aluminum","name":"Carpintería acristalada · azul gris","status":"criterio_visual","basis":"Composición 6+12A+6 documentada. Transparencia gráfica aplicada al objeto completo; marco y vidrio aún comparten malla.","physicalMaterialUnchanged":true} | ARQ-OF-20260710 · Arquitectura A101 / p. 3; Carpinterías A108 / p. 10, A109 / p. 11 | Ventana | 0.9 | 1.1 | Posición deducida de las cadenas de cotas en planta; diferencia de 100 mm al final de la cadena sur pendiente de revisión. Antepecho de +1,100 m según alzado A106. | Registro de líneas del PDF general, envolvente de 20 × 10 m; eje local 1 al norte y acceso del lado A al oeste. Estimación de trabajo de implantación de ±0,15 m, pendiente de CAD; no constituye una precisión topográfica garantizada. | ARQ-OF-20260710 · A109 / p. 11 | 285.95 | Carpintería acristalada · azul gris | glass_aluminum | [0.560784,0.682353,0.721569] | 0.2 | 0.1 | Composición 6+12A+6 documentada. Transparencia gráfica aplicada al objeto completo; marco y vidrio aún comparten malla. | El plano general de 2026-07-31 mantiene el edificio de oficinas de 200 m², mientras documentación anterior indica su supresión. Se conserva lo dibujado, pendiente de confirmación de la propiedad y del equipo de diseño.
Edificio de oficinas · ventana C0923_A_8 | Planos de arquitectura del edificio de oficinas; Planos de arquitectura del edificio de oficinas | Aluminio y acristalamiento 6+12A+6 | 0.9 × 0.045 × 2.3 | 287.05 | 289.35 | 0.09315 | office_0228 | 0.167164 | 0.897742 | 2.3 | 4.428 | 0.0931498 | office | Edificio de oficinas | {"name":"Aluminio y acristalamiento 6+12A+6","source":"ARQ-OF-20260710 · A109 / p. 11","status":"known"} | {"documented":[{"label":"Anchura del hueco","value":0.9,"unit":"m","source":"ARQ-OF-20260710 · Arquitectura A101 / p. 3; Carpinterías A108 / p. 10, A109 / p. 11","status":"documentado"},{"label":"Altura del hueco","value":2.3,"unit":"m","source":"ARQ-OF-20260710 · Arquitectura A101 / p. 3; Carpinterías A108 / p. 10, A109 / p. 11","status":"documentado"},{"label":"Altura de antepecho","value":1.1,"unit":"m","source":"ARQ-OF-20260710 · Arquitectura A101 / p. 3; Carpinterías A108 / p. 10, A109 / p. 11","status":"documentado"}],"geometry":[{"label":"Dimensiones de la caja local del elemento (X, Y, Z)","value":"0.9 × 0.045 × 2.3","unit":"m","source":"Malla triangulada del elemento en ejes locales del edificio","status":"derivado"},{"label":"Cota mínima absoluta de la malla","value":287.05,"unit":"m","source":"Malla de proyecto y origen altimétrico 285 m","status":"derivado"},{"label":"Cota máxima absoluta de la malla","value":289.35,"unit":"m","source":"Malla de proyecto y origen altimétrico 285 m","status":"derivado"},{"label":"Volumen geométrico bruto","value":0.09315,"unit":"m³","source":"Malla cerrada del elemento","status":"derivado"},{"label":"Espesor utilizado para representación","value":0.045,"unit":"m","source":"Hipótesis de visualización, no dimensión de fabricación","status":"provisional"}],"notes":["Las dimensiones documentadas proceden de anotaciones o cuadros; la caja y el volumen se calculan a partir de la malla.","El volumen es exclusivamente geométrico y bruto; no representa una medición neta de material ni una cantidad de compra."]} | {"documentId":"ARQ-OF-20260710","title":"Planos de arquitectura del edificio de oficinas","date":"2026-07-10","sheet":"Arquitectura A101 / p. 3; Carpinterías A108 / p. 10, A109 / p. 11"} | ["Posición deducida de las cadenas de cotas en planta; diferencia de 100 mm al final de la cadena sur pendiente de revisión. Antepecho de +1,100 m según alzado A106.","El plano general de 2026-07-31 mantiene el edificio de oficinas de 200 m², mientras documentación anterior indica su supresión. Se conserva lo dibujado, pendiente de confirmación de la propiedad y del equipo de diseño.","Elemento representado por un sólido cerrado único; perfiles de marco y hoja sin detalle de fabricación.","Registro de líneas del PDF general, envolvente de 20 × 10 m; eje local 1 al norte y acceso del lado A al oeste. Estimación de trabajo de implantación de ±0,15 m, pendiente de CAD; no constituye una precisión topográfica garantizada."] | {"horizontalStatus":"derivado","verticalStatus":"provisional","baseElevationM":285.95,"note":"Registro de líneas del PDF general, envolvente de 20 × 10 m; eje local 1 al norte y acceso del lado A al oeste. Estimación de trabajo de implantación de ±0,15 m, pendiente de CAD; no constituye una precisión topográfica garantizada."} | {"Pset_WindowCommon":{"IsExternal":{"value":true,"source":"ARQ-OF-20260710 · A101, A103 y alzados; elemento de la envolvente exterior identificada en planta","status":"known"}}} | {"boundingBoxM":{"min":[15.09283,74.524014,2.05],"max":[15.259994,75.421756,4.35]},"extentsM":[0.167164,0.897742,2.3],"meshSurfaceM2":4.427998,"meshVolumeM3":0.09315,"closedSolid":true,"basis":"Geometría triangulada releída del IFC; envolventes y magnitudes no contractuales."} | {"material":true,"document":true,"quantities":true,"containerGuid":"3ztlotcerHPueDgxP84R6z","containerName":"Planta baja"} | {"profileId":"glass_aluminum","name":"Carpintería acristalada · azul gris","materialName":"Aluminio y acristalamiento 6+12A+6","physicalMaterialStatus":"known","physicalMaterialSource":"ARQ-OF-20260710 · A109 / p. 11","appearanceStatus":"criterio_visual","appearanceBasis":"Composición 6+12A+6 documentada. Transparencia gráfica aplicada al objeto completo; marco y vidrio aún comparten malla.","note":"La apariencia gráfica no modifica ni confirma la especificación física del material."} | {"elementId":"office_0228","ifcGuid":"3clr9_hU5IqgbOEkxJPiYT","ifcClass":"IfcWindow","buildingId":"office","buildingName":"Edificio de oficinas","sourceDocumentId":"ARQ-OF-20260710","sourceRepresentationKind":"documentary_mesh"} | {"profileId":"glass_aluminum","name":"Carpintería acristalada · azul gris","status":"criterio_visual","basis":"Composición 6+12A+6 documentada. Transparencia gráfica aplicada al objeto completo; marco y vidrio aún comparten malla.","physicalMaterialUnchanged":true} | ARQ-OF-20260710 · Arquitectura A101 / p. 3; Carpinterías A108 / p. 10, A109 / p. 11 | Ventana | 0.9 | 1.1 | Posición deducida de las cadenas de cotas en planta; diferencia de 100 mm al final de la cadena sur pendiente de revisión. Antepecho de +1,100 m según alzado A106. | Registro de líneas del PDF general, envolvente de 20 × 10 m; eje local 1 al norte y acceso del lado A al oeste. Estimación de trabajo de implantación de ±0,15 m, pendiente de CAD; no constituye una precisión topográfica garantizada. | ARQ-OF-20260710 · A109 / p. 11 | 285.95 | Carpintería acristalada · azul gris | glass_aluminum | [0.560784,0.682353,0.721569] | 0.2 | 0.1 | Composición 6+12A+6 documentada. Transparencia gráfica aplicada al objeto completo; marco y vidrio aún comparten malla. | El plano general de 2026-07-31 mantiene el edificio de oficinas de 200 m², mientras documentación anterior indica su supresión. Se conserva lo dibujado, pendiente de confirmación de la propiedad y del equipo de diseño.
Edificio de oficinas · ventana C0923_1_1 | Planos de arquitectura del edificio de oficinas; Planos de arquitectura del edificio de oficinas | Aluminio y acristalamiento 6+12A+6 | 0.045 × 0.9 × 2.3 | 287.05 | 289.35 | 0.09315 | office_0229 | 0.897742 | 0.167164 | 2.3 | 4.428 | 0.0931497 | office | Edificio de oficinas | {"name":"Aluminio y acristalamiento 6+12A+6","source":"ARQ-OF-20260710 · A109 / p. 11","status":"known"} | {"documented":[{"label":"Anchura del hueco","value":0.9,"unit":"m","source":"ARQ-OF-20260710 · Arquitectura A101 / p. 3; Carpinterías A108 / p. 10, A109 / p. 11","status":"documentado"},{"label":"Altura del hueco","value":2.3,"unit":"m","source":"ARQ-OF-20260710 · Arquitectura A101 / p. 3; Carpinterías A108 / p. 10, A109 / p. 11","status":"documentado"},{"label":"Altura de antepecho","value":1.1,"unit":"m","source":"ARQ-OF-20260710 · Arquitectura A101 / p. 3; Carpinterías A108 / p. 10, A109 / p. 11","status":"documentado"}],"geometry":[{"label":"Dimensiones de la caja local del elemento (X, Y, Z)","value":"0.045 × 0.9 × 2.3","unit":"m","source":"Malla triangulada del elemento en ejes locales del edificio","status":"derivado"},{"label":"Cota mínima absoluta de la malla","value":287.05,"unit":"m","source":"Malla de proyecto y origen altimétrico 285 m","status":"derivado"},{"label":"Cota máxima absoluta de la malla","value":289.35,"unit":"m","source":"Malla de proyecto y origen altimétrico 285 m","status":"derivado"},{"label":"Volumen geométrico bruto","value":0.09315,"unit":"m³","source":"Malla cerrada del elemento","status":"derivado"},{"label":"Espesor utilizado para representación","value":0.045,"unit":"m","source":"Hipótesis de visualización, no dimensión de fabricación","status":"provisional"}],"notes":["Las dimensiones documentadas proceden de anotaciones o cuadros; la caja y el volumen se calculan a partir de la malla.","El volumen es exclusivamente geométrico y bruto; no representa una medición neta de material ni una cantidad de compra."]} | {"documentId":"ARQ-OF-20260710","title":"Planos de arquitectura del edificio de oficinas","date":"2026-07-10","sheet":"Arquitectura A101 / p. 3; Carpinterías A108 / p. 10, A109 / p. 11"} | ["Posición deducida de las cadenas de cotas en planta; diferencia de 100 mm al final de la cadena sur pendiente de revisión. Antepecho de +1,100 m según alzado A106.","El plano general de 2026-07-31 mantiene el edificio de oficinas de 200 m², mientras documentación anterior indica su supresión. Se conserva lo dibujado, pendiente de confirmación de la propiedad y del equipo de diseño.","Elemento representado por un sólido cerrado único; perfiles de marco y hoja sin detalle de fabricación.","Registro de líneas del PDF general, envolvente de 20 × 10 m; eje local 1 al norte y acceso del lado A al oeste. Estimación de trabajo de implantación de ±0,15 m, pendiente de CAD; no constituye una precisión topográfica garantizada."] | {"horizontalStatus":"derivado","verticalStatus":"provisional","baseElevationM":285.95,"note":"Registro de líneas del PDF general, envolvente de 20 × 10 m; eje local 1 al norte y acceso del lado A al oeste. Estimación de trabajo de implantación de ±0,15 m, pendiente de CAD; no constituye una precisión topográfica garantizada."} | {"Pset_WindowCommon":{"IsExternal":{"value":true,"source":"ARQ-OF-20260710 · A101, A103 y alzados; elemento de la envolvente exterior identificada en planta","status":"known"}}} | {"boundingBoxM":{"min":[22.479354,91.992866,2.05],"max":[23.377096,92.16003,4.35]},"extentsM":[0.897742,0.167164,2.3],"meshSurfaceM2":4.428,"meshVolumeM3":0.09315,"closedSolid":true,"basis":"Geometría triangulada releída del IFC; envolventes y magnitudes no contractuales."} | {"material":true,"document":true,"quantities":true,"containerGuid":"3ztlotcerHPueDgxP84R6z","containerName":"Planta baja"} | {"profileId":"glass_aluminum","name":"Carpintería acristalada · azul gris","materialName":"Aluminio y acristalamiento 6+12A+6","physicalMaterialStatus":"known","physicalMaterialSource":"ARQ-OF-20260710 · A109 / p. 11","appearanceStatus":"criterio_visual","appearanceBasis":"Composición 6+12A+6 documentada. Transparencia gráfica aplicada al objeto completo; marco y vidrio aún comparten malla.","note":"La apariencia gráfica no modifica ni confirma la especificación física del material."} | {"elementId":"office_0229","ifcGuid":"3ZECJyGcnTN9$7su63xX9t","ifcClass":"IfcWindow","buildingId":"office","buildingName":"Edificio de oficinas","sourceDocumentId":"ARQ-OF-20260710","sourceRepresentationKind":"documentary_mesh"} | {"profileId":"glass_aluminum","name":"Carpintería acristalada · azul gris","status":"criterio_visual","basis":"Composición 6+12A+6 documentada. Transparencia gráfica aplicada al objeto completo; marco y vidrio aún comparten malla.","physicalMaterialUnchanged":true} | ARQ-OF-20260710 · Arquitectura A101 / p. 3; Carpinterías A108 / p. 10, A109 / p. 11 | Ventana | 0.9 | 1.1 | Posición deducida de las cadenas de cotas en planta; diferencia de 100 mm al final de la cadena sur pendiente de revisión. Antepecho de +1,100 m según alzado A106. | Registro de líneas del PDF general, envolvente de 20 × 10 m; eje local 1 al norte y acceso del lado A al oeste. Estimación de trabajo de implantación de ±0,15 m, pendiente de CAD; no constituye una precisión topográfica garantizada. | ARQ-OF-20260710 · A109 / p. 11 | 285.95 | Carpintería acristalada · azul gris | glass_aluminum | [0.560784,0.682353,0.721569] | 0.2 | 0.1 | Composición 6+12A+6 documentada. Transparencia gráfica aplicada al objeto completo; marco y vidrio aún comparten malla. | El plano general de 2026-07-31 mantiene el edificio de oficinas de 200 m², mientras documentación anterior indica su supresión. Se conserva lo dibujado, pendiente de confirmación de la propiedad y del equipo de diseño.
Edificio de oficinas · ventana C0923_1_2 | Planos de arquitectura del edificio de oficinas; Planos de arquitectura del edificio de oficinas | Aluminio y acristalamiento 6+12A+6 | 0.045 × 0.9 × 2.3 | 287.05 | 289.35 | 0.09315 | office_0230 | 0.897742 | 0.167164 | 2.3 | 4.428 | 0.0931498 | office | Edificio de oficinas | {"name":"Aluminio y acristalamiento 6+12A+6","source":"ARQ-OF-20260710 · A109 / p. 11","status":"known"} | {"documented":[{"label":"Anchura del hueco","value":0.9,"unit":"m","source":"ARQ-OF-20260710 · Arquitectura A101 / p. 3; Carpinterías A108 / p. 10, A109 / p. 11","status":"documentado"},{"label":"Altura del hueco","value":2.3,"unit":"m","source":"ARQ-OF-20260710 · Arquitectura A101 / p. 3; Carpinterías A108 / p. 10, A109 / p. 11","status":"documentado"},{"label":"Altura de antepecho","value":1.1,"unit":"m","source":"ARQ-OF-20260710 · Arquitectura A101 / p. 3; Carpinterías A108 / p. 10, A109 / p. 11","status":"documentado"}],"geometry":[{"label":"Dimensiones de la caja local del elemento (X, Y, Z)","value":"0.045 × 0.9 × 2.3","unit":"m","source":"Malla triangulada del elemento en ejes locales del edificio","status":"derivado"},{"label":"Cota mínima absoluta de la malla","value":287.05,"unit":"m","source":"Malla de proyecto y origen altimétrico 285 m","status":"derivado"},{"label":"Cota máxima absoluta de la malla","value":289.35,"unit":"m","source":"Malla de proyecto y origen altimétrico 285 m","status":"derivado"},{"label":"Volumen geométrico bruto","value":0.09315,"unit":"m³","source":"Malla cerrada del elemento","status":"derivado"},{"label":"Espesor utilizado para representación","value":0.045,"unit":"m","source":"Hipótesis de visualización, no dimensión de fabricación","status":"provisional"}],"notes":["Las dimensiones documentadas proceden de anotaciones o cuadros; la caja y el volumen se calculan a partir de la malla.","El volumen es exclusivamente geométrico y bruto; no representa una medición neta de material ni una cantidad de compra."]} | {"documentId":"ARQ-OF-20260710","title":"Planos de arquitectura del edificio de oficinas","date":"2026-07-10","sheet":"Arquitectura A101 / p. 3; Carpinterías A108 / p. 10, A109 / p. 11"} | ["Posición deducida de las cadenas de cotas en planta; diferencia de 100 mm al final de la cadena sur pendiente de revisión. Antepecho de +1,100 m según alzado A106.","El plano general de 2026-07-31 mantiene el edificio de oficinas de 200 m², mientras documentación anterior indica su supresión. Se conserva lo dibujado, pendiente de confirmación de la propiedad y del equipo de diseño.","Elemento representado por un sólido cerrado único; perfiles de marco y hoja sin detalle de fabricación.","Registro de líneas del PDF general, envolvente de 20 × 10 m; eje local 1 al norte y acceso del lado A al oeste. Estimación de trabajo de implantación de ±0,15 m, pendiente de CAD; no constituye una precisión topográfica garantizada."] | {"horizontalStatus":"derivado","verticalStatus":"provisional","baseElevationM":285.95,"note":"Registro de líneas del PDF general, envolvente de 20 × 10 m; eje local 1 al norte y acceso del lado A al oeste. Estimación de trabajo de implantación de ±0,15 m, pendiente de CAD; no constituye una precisión topográfica garantizada."} | {"Pset_WindowCommon":{"IsExternal":{"value":true,"source":"ARQ-OF-20260710 · A101, A103 y alzados; elemento de la envolvente exterior identificada en planta","status":"known"}}} | {"boundingBoxM":{"min":[24.26258,91.747699,2.05],"max":[25.160322,91.914863,4.35]},"extentsM":[0.897742,0.167164,2.3],"meshSurfaceM2":4.427998,"meshVolumeM3":0.09315,"closedSolid":true,"basis":"Geometría triangulada releída del IFC; envolventes y magnitudes no contractuales."} | {"material":true,"document":true,"quantities":true,"containerGuid":"3ztlotcerHPueDgxP84R6z","containerName":"Planta baja"} | {"profileId":"glass_aluminum","name":"Carpintería acristalada · azul gris","materialName":"Aluminio y acristalamiento 6+12A+6","physicalMaterialStatus":"known","physicalMaterialSource":"ARQ-OF-20260710 · A109 / p. 11","appearanceStatus":"criterio_visual","appearanceBasis":"Composición 6+12A+6 documentada. Transparencia gráfica aplicada al objeto completo; marco y vidrio aún comparten malla.","note":"La apariencia gráfica no modifica ni confirma la especificación física del material."} | {"elementId":"office_0230","ifcGuid":"3RmupqWwTTihBbdJXsdC0c","ifcClass":"IfcWindow","buildingId":"office","buildingName":"Edificio de oficinas","sourceDocumentId":"ARQ-OF-20260710","sourceRepresentationKind":"documentary_mesh"} | {"profileId":"glass_aluminum","name":"Carpintería acristalada · azul gris","status":"criterio_visual","basis":"Composición 6+12A+6 documentada. Transparencia gráfica aplicada al objeto completo; marco y vidrio aún comparten malla.","physicalMaterialUnchanged":true} | ARQ-OF-20260710 · Arquitectura A101 / p. 3; Carpinterías A108 / p. 10, A109 / p. 11 | Ventana | 0.9 | 1.1 | Posición deducida de las cadenas de cotas en planta; diferencia de 100 mm al final de la cadena sur pendiente de revisión. Antepecho de +1,100 m según alzado A106. | Registro de líneas del PDF general, envolvente de 20 × 10 m; eje local 1 al norte y acceso del lado A al oeste. Estimación de trabajo de implantación de ±0,15 m, pendiente de CAD; no constituye una precisión topográfica garantizada. | ARQ-OF-20260710 · A109 / p. 11 | 285.95 | Carpintería acristalada · azul gris | glass_aluminum | [0.560784,0.682353,0.721569] | 0.2 | 0.1 | Composición 6+12A+6 documentada. Transparencia gráfica aplicada al objeto completo; marco y vidrio aún comparten malla. | El plano general de 2026-07-31 mantiene el edificio de oficinas de 200 m², mientras documentación anterior indica su supresión. Se conserva lo dibujado, pendiente de confirmación de la propiedad y del equipo de diseño.
